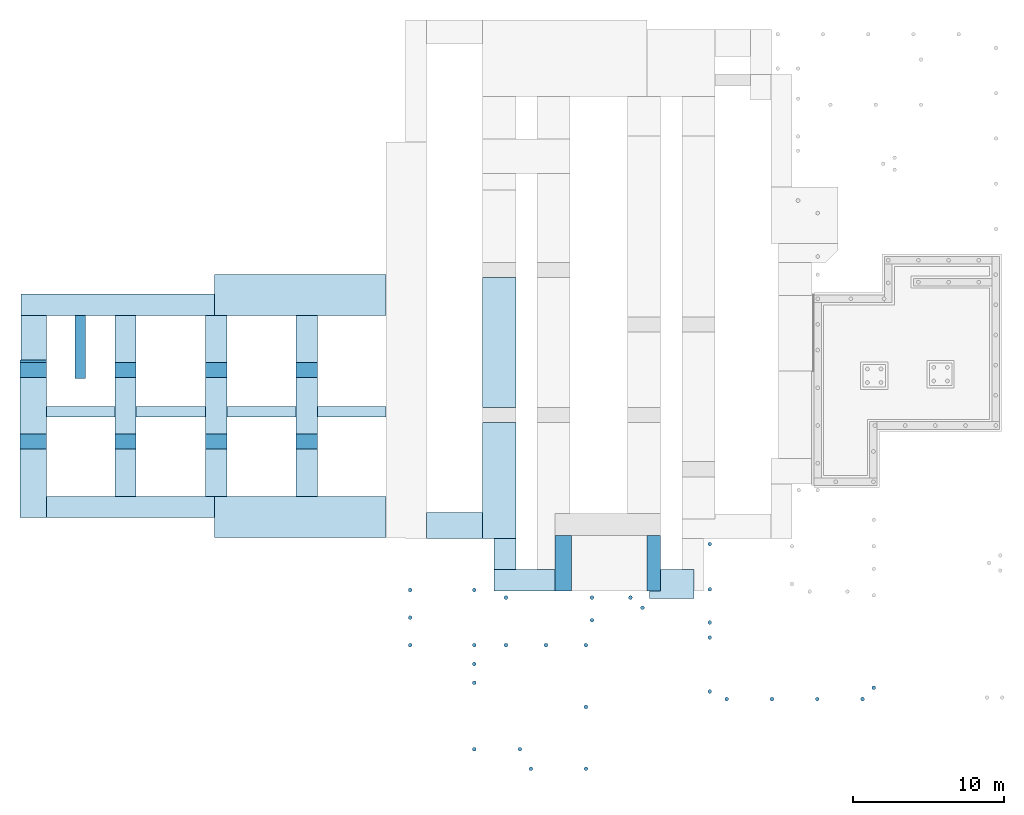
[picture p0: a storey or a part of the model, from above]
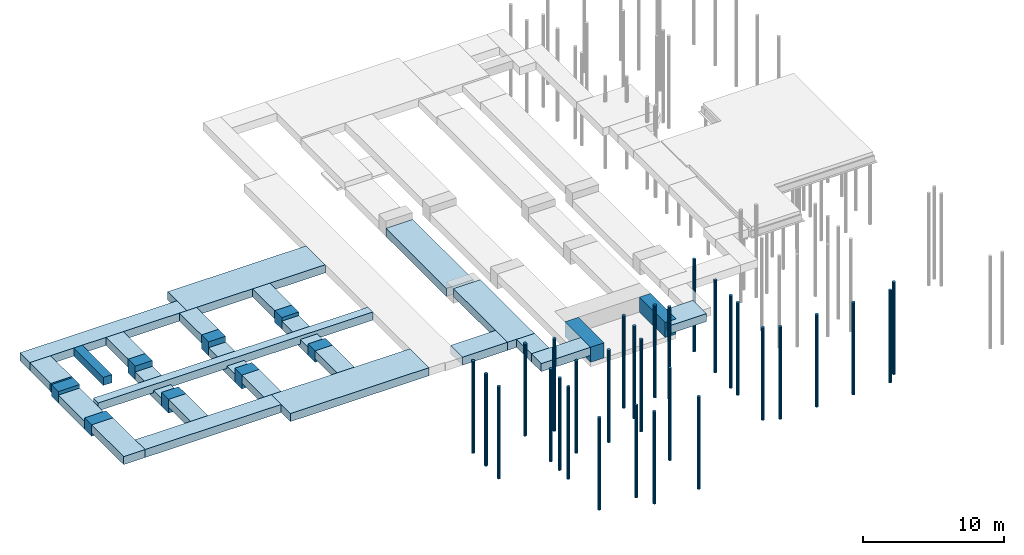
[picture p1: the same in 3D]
Properties of the parts of a building model (IFC4), part 1 of 45

# File
Description: no view
File name: 604-SOKOLOV_ASR_3D_f.ifc
Time: 2023-04-14T09:23:47
Author: Jahodová Jana
Organization: TECHNICO Opava s.r.o., Hradecká 51
Written by: EDMsix Version 2.0.209.92 Dec 12 2020
Made in: Allplan 2022.1 07.06.2022 - 21:35:19

# IfcSite, 3. ASŘ
RefLatitude: 48, 0, 0, 0; RefLongitude: 0, 0, 0, 0

# IfcBuildingStorey (13)
Name | In | Elevation (m)
Půdorys 1.PP | Pavilon B | -3.3
Půdorys 1.NP | Pavilon B | 0
Půdorys 2.NP | Pavilon B | 3.6
Výkopy | Pavilon C | 0
Základy | Pavilon C | -4.4
Půdorys 1.PP | Pavilon C | -3.3
Půdorys 1.NP | Pavilon C | 0
Půdorys 2.NP | Pavilon C | 3.6
Půdorys 3.NP | Pavilon C | 7.2
Půdorys 4.NP | Pavilon C | 10.5
Půdorys 5.NP | Pavilon C | 13.8
Půdorys 6.NP | Pavilon C | 17.8
Půdorys střechy | Pavilon C | 20.83

# IfcSpace (98)
NEMSOK - Typ obestavění: a; Typ plochy DIN 277: N; Typ plochy obytná plocha: WO; BauNVO_Anrechnung_auf_GR: 0; Typ využití DIN 277: NF; BauNVO_Anrechnung_auf_GF: 0; Místnost pod schodištěm (obytná plocha od 2m): 0; Faktor_obytné_plochy_místnosti: 1; Faktor_DIN277: 1; Jednotka: m3; Název_objektu: Místnost
Name | In | LongName | Kód_umístění-označení_podlaží | Name | Profile | Grade | Finish | CogZ | CogX = EndZ | Top_Elevation | EndY | Allright_Stavebni_dil_ID | NetFloorArea (m2) | GrossFloorArea (m2) | GrossWallArea (m2) | NetWallArea (m2) | NetPerimeter (m) | GrossVolume (m3) | NetVolume (m3) | FinishCeilingHeight (m) | FinishFloorHeight (m) | Group
-1.34 | Půdorys 1.PP | CHODBA | 1.PP | P02 | keramická dlažba | TVO, T03 | VSO, KO | LAMINÁT | ŠTUKOVÁ OMÍTKA | 0 | PODLAHOVÁ LIŠTA | 1369Mís0000000006 | 76.24 | 76.24 | 212.28 | 195.812 | 69.6 | 232.532 | 222.621 | 2.92 | 0.1 | ČÁST A | NEMSOK - Status: Nový; Text1: OPĚRNÉ MADLO
-1.35 | Půdorys 1.PP | EEG | 1.PP |  |  |  |  |  |  |  |  | 1369Mís0000000012 | 16.165 | 16.165 | 52.612 | 52.614 | 17.25 | 49.303 | 47.202 | 2.92 | 0.1 | ČÁST A | NEMSOK - Status: Nový; Text1: KERAMICKÝ OBKLAD
-1.39 | Půdorys 1.PP | INTERNÍ AMBULANCE | 1.PP | P02 | keramická dlažba | TVO, T03 | VSO, KO | LAMINÁT | ŠTUKOVÁ OMÍTKA | 0 | PODLAHOVÁ LIŠTA | 1369Mís0000000054 | 15.486 | 15.485 | 50.63 | 50.631 | 16.6 | 47.229 | 45.216 | 2.92 | 0.1 | ČÁST A | NEMSOK - Status: Nový; Text1: KERAMICKÝ OBKLAD
-1.46 | Půdorys 1.PP | PRAKTICKÝ LÉKAŘ | 1.PP | P02 | keramická dlažba | TVO, T03 | VSO, KO | LAMINÁT | ŠTUKOVÁ OMÍTKA | 0 | PODLAHOVÁ LIŠTA | 1369Mís0000000139 | 17.289 | 17.289 | 66.49 | 66.492 | 21.8 | 52.733 | 50.485 | 2.92 | 0.1 | ČÁST A | NEMSOK - Status: Nový; Text1: KERAMICKÝ OBKLAD
-1.47 | Půdorys 1.PP | WC MUŽI PERSONÁL - PŘEDSÍŇ | 1.PP | P02 | keramická dlažba | TVO, T03 | VSO, KO | LAMINÁT | ŠTUKOVÁ OMÍTKA | 0 | PODLAHOVÁ LIŠTA | 1369Mís0000000148 | 1.77 | 1.77 | 16.775 | 16.777 | 5.5 | 5.399 | 5.168 | 2.92 | 0.1 | ČÁST A | NEMSOK - Status: Nový
-1.48 | Půdorys 1.PP | WC MUŽI PERSONÁL | 1.PP | P02 | keramická dlažba | TVO, T03 | VSO, KO | LAMINÁT | ŠTUKOVÁ OMÍTKA | 0 | PODLAHOVÁ LIŠTA | 1369Mís0000000157 | 1.61 | 1.61 | 15.555 | 15.555 | 5.1 | 4.911 | 4.701 | 2.92 | 0.1 | ČÁST A | NEMSOK - Status: Nový
-1.49 | Půdorys 1.PP | PRAKTICKÝ LÉKAŘ - SESTERNA | 1.PP | P02 | keramická dlažba | TVO, T03 | VSO, KO | LAMINÁT | ŠTUKOVÁ OMÍTKA | 0 | PODLAHOVÁ LIŠTA | 1369Mís0000000168 | 20.669 | 20.668 | 63.898 | 63.899 | 20.95 | 63.038 | 60.351 | 2.92 | 0.1 | ČÁST A | NEMSOK - Status: Nový; Text1: KERAMICKÝ OBKLAD
-1.50 | Půdorys 1.PP | MAMOSCREENING - MAMOGRAF | 1.PP | P02 | keramická dlažba | TVO, T03 | VSO, KO | LAMINÁT | ŠTUKOVÁ OMÍTKA | 0 | PODLAHOVÁ LIŠTA | 1369Mís0000000177 | 20.711 | 20.711 | 59.322 | 59.323 | 19.45 | 63.169 | 60.166 | 2.905 | 0.1 | ČÁST A | NEMSOK - Status: Nový; Text1: KERAMICKÝ OBKLAD
-1.51 | Půdorys 1.PP | MAMOSCREENING - POPISOVNA | 1.PP | P02 | keramická dlažba | TVO, T03 | VSO, KO | LAMINÁT | ŠTUKOVÁ OMÍTKA | 0 | PODLAHOVÁ LIŠTA | 1369Mís0000000188 | 17.4 | 17.4 | 54.29 | 54.291 | 17.8 | 53.07 | 50.808 | 2.92 | 0.1 | ČÁST A | NEMSOK - Status: Nový; Text1: KERAMICKÝ OBKLAD
-1.52 | Půdorys 1.PP | MAMOSCREENING - SONO | 1.PP | P02 | keramická dlažba | TVO, T03 | VSO, KO | LAMINÁT | ŠTUKOVÁ OMÍTKA | 0 | PODLAHOVÁ LIŠTA | 1369Mís0000000197 | 17.27 | 17.27 | 50.783 | 50.783 | 16.65 | 52.674 | 50.428 | 2.92 | 0.1 | ČÁST A | NEMSOK - Status: Nový; Text1: KERAMICKÝ OBKLAD
-1.53 | Půdorys 1.PP | MAMOSCREENING - ČEKÁRNA | 1.PP | P02 | keramická dlažba | TVO, T03 | VSO, KO | LAMINÁT | ŠTUKOVÁ OMÍTKA | 0 | PODLAHOVÁ LIŠTA | 1369Mís0000000206 | 36.652 | 36.652 | 119.712 | 119.715 | 39.25 | 111.787 | 107.023 | 2.92 | 0.1 | ČÁST A | NEMSOK - Status: Nový; Text1: KERAMICKÝ OBKLAD
-1.55 | Půdorys 1.PP | HLAVNÍ JISTIČ | 1.PP | P02 | keramická dlažba | TVO, T03 | VSO, KO | LAMINÁT | ŠTUKOVÁ OMÍTKA | 0 | PODLAHOVÁ LIŠTA | 1369Mís0000000215 | 11.2 | 11.199 | 42.7 | 42.7 | 14 | 34.158 | 32.814 | 2.93 | 0.1 | ČÁST A | NEMSOK - Status: Nový
-1.56 | Půdorys 1.PP | WC ŽENY PERSONÁL - PŘEDSÍŇ | 1.PP | P02 | keramická dlažba | TVO, T03 | VSO, KO | LAMINÁT | ŠTUKOVÁ OMÍTKA | 0 | PODLAHOVÁ LIŠTA | 1369Mís0000000224 | 1.93 | 1.93 | 17.049 | 17.05 | 5.59 | 5.886 | 5.635 | 2.92 | 0.1 | ČÁST A | NEMSOK - Status: Nový
-1.56a | Půdorys 1.PP | WC ŽENY PERSONÁL | 1.PP | P02 | keramická dlažba | TVO, T03 | VSO, KO | LAMINÁT | ŠTUKOVÁ OMÍTKA | 0 | PODLAHOVÁ LIŠTA | 1369Mís0000000233 | 1.537 | 1.537 | 15.128 | 15.129 | 4.96 | 4.689 | 4.489 | 2.92 | 0.1 | ČÁST A | NEMSOK - Status: Nový
-1.40 | Půdorys 1.PP | WC MUŽI - PŘEDSÍŇ | 1.PP | P02 | keramická dlažba | TVO, T03 | VSO, KO | LAMINÁT | ŠTUKOVÁ OMÍTKA | 0 | PODLAHOVÁ LIŠTA | 1369Mís0000000367 | 4.923 | 4.922 | 33.855 | 33.856 | 11.1 | 15.014 | 14.373 | 2.92 | 0.1 | ČÁST A | NEMSOK - Status: Nový
-1.41 | Půdorys 1.PP | WC MUŽI | 1.PP | P02 | keramická dlažba | TVO, T03 | VSO, KO | LAMINÁT | ŠTUKOVÁ OMÍTKA | 0 | PODLAHOVÁ LIŠTA | 1369Mís0000000378 | 1.148 | 1.148 | 13.268 | 10.523 | 4.35 | 3.5 | 3.351 | 2.92 | 0.1 | ČÁST A | NEMSOK - Status: Nový
-1.42 | Půdorys 1.PP | WC ZTP | 1.PP | P02 | keramická dlažba | TVO, T03 | VSO, KO | LAMINÁT | ŠTUKOVÁ OMÍTKA | 0 | PODLAHOVÁ LIŠTA | 1369Mís0000000387 | 4.07 | 4.07 | 26.535 | 26.536 | 8.7 | 12.413 | 11.884 | 2.92 | 0.1 | ČÁST A | NEMSOK - Status: Nový
-1.43 | Půdorys 1.PP | WC ŽENY - PŘEDSÍŇ | 1.PP | P02 | keramická dlažba | TVO, T03 | VSO, KO | LAMINÁT | ŠTUKOVÁ OMÍTKA | 0 | PODLAHOVÁ LIŠTA | 1369Mís0000000396 | 2.43 | 2.43 | 19.215 | 19.215 | 6.3 | 7.412 | 7.096 | 2.92 | 0.1 | ČÁST A | NEMSOK - Status: Nový
-1.44 | Půdorys 1.PP | WC ŽENY | 1.PP | P02 | keramická dlažba | TVO, T03 | VSO, KO | LAMINÁT | ŠTUKOVÁ OMÍTKA | 0 | PODLAHOVÁ LIŠTA | 1369Mís0000000405 | 1.485 | 1.485 | 15.555 | 15.555 | 5.1 | 4.529 | 4.336 | 2.92 | 0.1 | ČÁST A | NEMSOK - Status: Nový
-1.45 | Půdorys 1.PP | WC ŽENY | 1.PP | P02 | keramická dlažba | TVO, T03 | VSO, KO | LAMINÁT | ŠTUKOVÁ OMÍTKA | 0 | PODLAHOVÁ LIŠTA | 1369Mís0000000416 | 2.025 | 2.025 | 19.825 | 19.826 | 6.5 | 6.176 | 5.913 | 2.92 | 0.1 | ČÁST A | NEMSOK - Status: Nový
-1.54 | Půdorys 1.PP | TECHNOLOGIE | 1.PP | P02 | keramická dlažba | TVO, T03 | VSO, KO | LAMINÁT | ŠTUKOVÁ OMÍTKA | 0 | PODLAHOVÁ LIŠTA | 1369Mís0000000514 | 1.305 | 1.305 | 15.402 | 15.403 | 5.05 | 3.98 | 3.824 | 2.93 | 0.1 | ČÁST A | NEMSOK - Status: Nový
-1.05 | Půdorys 1.PP | STROJOVNA VZT | 1.PP | P02 | keramická dlažba | TVO, T03 | VSO, KO | LAMINÁT | ŠTUKOVÁ OMÍTKA | 0 | PODLAHOVÁ LIŠTA | 1369Mís0000001178 | 22.984 | 22.985 | 64.163 | 64.165 | 21.75 | 67.806 | 64.359 | 2.8 | 0.1 | ČÁST A | NEMSOK - Text1: AKUSTICKÝ OBKLAD
-1.57 | Půdorys 1.PP | ÚKLIDOVÁ KOMORA | 1.PP | P02 | keramická dlažba | TVO, T03 | VSO, KO | LAMINÁT | ŠTUKOVÁ OMÍTKA | 0 | PODLAHOVÁ LIŠTA | 1369Mís0000001551 | 3.026 | 3.026 | 21.777 | 21.778 | 7.14 | 9.229 | 8.836 | 2.92 | 0.1 | ČÁST A | NEMSOK - Status: Nový
-1.41 | Půdorys 1.PP | WC MUŽI | 1.PP | P02 | keramická dlažba | TVO, T03 | VSO, KO | LAMINÁT | ŠTUKOVÁ OMÍTKA | 0 | PODLAHOVÁ LIŠTA | 1369Mís0000001767 | 3.47 | 3.47 | 24.095 | 21.351 | 7.9 | 10.584 | 10.132 | 2.92 | 0.1 | ČÁST A | NEMSOK - Status: Nový
-1.38 | Půdorys 1.PP | ČEKÁRNA | 1.PP | P02 | keramická dlažba | TVO, T03 | VSO, KO | LAMINÁT | ŠTUKOVÁ OMÍTKA | 0 | PODLAHOVÁ LIŠTA | 1369Mís0000000043 | 28.459 | 28.459 | 67.862 | 51.393 | 22.25 | 86.801 | 83.101 | 2.92 | 0.1 | ČÁST A | NEMSOK - Status: Nový
-1.36 | Půdorys 1.PP | EMG | 1.PP | P02 | keramická dlažba | TVO, T03 | VSO, KO | LAMINÁT | ŠTUKOVÁ OMÍTKA | 0 | PODLAHOVÁ LIŠTA | 1369Mís0000000023 | 16.165 | 16.165 | 52.613 | 52.614 | 17.25 | 49.303 | 47.202 | 2.92 | 0.1 | ČÁST A | NEMSOK - Status: Nový; Text1: KERAMICKÝ OBKLAD
-1.37 | Půdorys 1.PP | SONO | 1.PP | P02 | keramická dlažba | TVO, T03 | VSO, KO | LAMINÁT | ŠTUKOVÁ OMÍTKA | 0 | PODLAHOVÁ LIŠTA | 1369Mís0000000034 | 24.09 | 24.09 | 61.915 | 61.917 | 20.3 | 73.475 | 70.343 | 2.92 | 0.1 | ČÁST A | NEMSOK - Status: Nový; Text1: KERAMICKÝ OBKLAD
-1.58 | Půdorys 1.PP | CHODBA | 1.PP | P02 | keramická dlažba | TVO, T03 | VSO, KO | LAMINÁT | ŠTUKOVÁ OMÍTKA | 0 | PODLAHOVÁ LIŠTA | 1369Mís0000000539 | 7.41 | 7.41 | 40.412 | 36.753 | 13.25 | 22.601 | 21.526 | 2.905 | 0.1 | ČÁST B
-1.64 | Půdorys 1.PP | CHODBA | 1.PP | P02 | keramická dlažba | TVO, T03 | VSO, KO | LAMINÁT | ŠTUKOVÁ OMÍTKA | 0 | PODLAHOVÁ LIŠTA | 1369Mís0000000548 | 9.076 | 9.075 | 45.597 | 45.598 | 14.95 | 27.679 | 26.318 | 2.9 | 0.1 | ČÁST B
-1.60 | Půdorys 1.PP | INSTALAČNÍ CHODBA VZT | 1.PP | P02 | keramická dlažba | TVO, T03 | VSO, KO | LAMINÁT | ŠTUKOVÁ OMÍTKA | 0 | PODLAHOVÁ LIŠTA | 1369Mís0000000557 | 8.352 | 8.352 | 52.787 | 52.788 | 16.242 | 27.145 | 24.598 | 2.945 | 0.3 | ČÁST B
-1.61 | Půdorys 1.PP | KANCELÁŘ VRCHNÍ SESTRY | 1.PP | P02 | keramická dlažba | TVO, T03 | VSO, KO | LAMINÁT | ŠTUKOVÁ OMÍTKA | 0 | PODLAHOVÁ LIŠTA | 1369Mís0000000566 | 16.75 | 16.75 | 54.275 | 54.275 | 16.7 | 54.438 | 48.91 | 2.92 | 0.3 | ČÁST B | NEMSOK - Text1: KERAMICKÝ OBKLAD
-1.62 | Půdorys 1.PP | DENNÍ MÍSTNOST | 1.PP | P02 | keramická dlažba | TVO, T03 | VSO, KO | LAMINÁT | ŠTUKOVÁ OMÍTKA | 0 | PODLAHOVÁ LIŠTA | 1369Mís0000000575 | 28.32 | 28.32 | 78 | 78.002 | 24 | 92.04 | 82.694 | 2.92 | 0.3 | ČÁST B | NEMSOK - Text1: KERAMICKÝ OBKLAD
-1.63 | Půdorys 1.PP | STROJOVNA VZT | 1.PP | P02 | keramická dlažba | TVO, T03 | VSO, KO | LAMINÁT | ŠTUKOVÁ OMÍTKA | 0 | PODLAHOVÁ LIŠTA | 1369Mís0000000584 | 51.486 | 51.486 | 144.56 | 144.56 | 44.48 | 167.331 | 149.311 | 2.9 | 0.3 | ČÁST B
-1.59 | Půdorys 1.PP | TECHNICKÁ MÍSTNOST ELEKTRO | 1.PP | P02 | keramická dlažba | TVO, T03 | VSO, KO | LAMINÁT | ŠTUKOVÁ OMÍTKA | 0 | PODLAHOVÁ LIŠTA | 1369Mís0000000599 | 22.61 | 22.61 | 59.475 | 59.476 | 19.5 | 68.961 | 66.248 | 2.93 | 0.1 | ČÁST B | NEMSOK - Text1: DOPLNĚNÍ OMÍTKY
-1.19 | Půdorys 1.PP | SKLAD STERILNÍHO MATERIÁLU | 1.PP | P02 | keramická dlažba | TVO, T03 | VSO, KO | LAMINÁT | ŠTUKOVÁ OMÍTKA | 0 | PODLAHOVÁ LIŠTA | 1369Mís0000000879 | 85.169 | 85.167 | 122.915 | 122.918 | 40.3 | 259.761 | 248.69 | 2.92 | 0.1 | ČÁST B | NEMSOK - Status: Nespecifikovaný; Text1: DOPLNĚNÍ KERAM. OBKLADU
-1.58 | Půdorys 1.PP | CHODBA | 1.PP | P02 | keramická dlažba | TVO, T03 | VSO, KO | LAMINÁT | ŠTUKOVÁ OMÍTKA | 0 | PODLAHOVÁ LIŠTA | 1369Mís0000001088 | 13.982 | 13.982 | 65.325 | 61.667 | 20.1 | 45.441 | 40.616 | 2.905 | 0.3 | ČÁST B
-1.02 | Půdorys 1.PP | CHODBA | 1.PP | P02 | keramická dlažba | TVO, T03 | VSO, KO | LAMINÁT | ŠTUKOVÁ OMÍTKA | 0 | PODLAHOVÁ LIŠTA | 1369Mís0000001285 | 41.014 | 41.014 | 117.41 | 117.412 | 39.8 | 120.991 | 119.556 | 2.915 | 0.005 | ČÁST B | NEMSOK - Text1: DŘEVĚNÉ MADLO
1.01 | Půdorys 1.NP | SPOJOVACÍ CHODBA | 1.NP | P02 | keramická dlažba | TVO, T03 | VSO, KO | LAMINÁT | ŠTUKOVÁ OMÍTKA | 0 | PODLAHOVÁ LIŠTA | 1469Mís0000000353 | 48.806 | 48.805 | 149.912 | 139.528 | 44.75 | 163.497 | 157.152 | 3.22 | 0.1 | KAVÁRNA
K1.09 | Půdorys 1.NP | PŘÍPRAVNA STUDENÉ KUCHYNĚ | 1.NP | P02 | keramická dlažba | TVO, T03 | VSO, KO | LAMINÁT | ŠTUKOVÁ OMÍTKA | 0 | PODLAHOVÁ LIŠTA | 1469Mís0000000427 | 19.335 | 19.334 | 74.55 | 74.551 | 21 | 68.636 | 62.256 | 3.22 | 0.3 | KAVÁRNA
K1.10 | Půdorys 1.NP | SKLAD | 1.NP | P02 | keramická dlažba | TVO, T03 | VSO, KO | LAMINÁT | ŠTUKOVÁ OMÍTKA | 0 | PODLAHOVÁ LIŠTA | 1469Mís0000000439 | 6.919 | 6.919 | 38.517 | 38.518 | 10.85 | 24.562 | 22.278 | 3.22 | 0.3 | KAVÁRNA
K1.12 | Půdorys 1.NP | ÚKLID | 1.NP | P02 | keramická dlažba | TVO, T03 | VSO, KO | LAMINÁT | ŠTUKOVÁ OMÍTKA | 0 | PODLAHOVÁ LIŠTA | 1469Mís0000000448 | 2.031 | 2.031 | 20.413 | 20.413 | 5.75 | 7.211 | 6.541 | 3.22 | 0.3 | KAVÁRNA
K1.11 | Půdorys 1.NP | CHODBA | 1.NP | P02 | keramická dlažba | TVO, T03 | VSO, KO | LAMINÁT | ŠTUKOVÁ OMÍTKA | 0 | PODLAHOVÁ LIŠTA | 1469Mís0000000459 | 5.025 | 5.025 | 34.435 | 34.435 | 9.7 | 17.839 | 16.181 | 3.22 | 0.3 | KAVÁRNA
K1.13 | Půdorys 1.NP | ŠATNA | 1.NP | P02 | keramická dlažba | TVO, T03 | VSO, KO | LAMINÁT | ŠTUKOVÁ OMÍTKA | 0 | PODLAHOVÁ LIŠTA | 1469Mís0000000470 | 3.5 | 3.5 | 26.625 | 26.625 | 7.5 | 12.425 | 11.27 | 3.22 | 0.3 | KAVÁRNA
K1.14a | Půdorys 1.NP | WC ZAMĚSTNANCI | 1.NP | P02 | keramická dlažba | TVO, T03 | VSO, KO | LAMINÁT | ŠTUKOVÁ OMÍTKA | 0 | PODLAHOVÁ LIŠTA | 1469Mís0000000481 | 1.327 | 1.327 | 16.862 | 16.863 | 4.75 | 4.713 | 4.275 | 3.22 | 0.3 | KAVÁRNA
K1.14 | Půdorys 1.NP | WC PŘEDSÍŇ ZAMĚSTNANCI | 1.NP | P02 | keramická dlažba | TVO, T03 | VSO, KO | LAMINÁT | ŠTUKOVÁ OMÍTKA | 0 | PODLAHOVÁ LIŠTA | 1469Mís0000000490 | 3.631 | 3.631 | 27.157 | 27.158 | 7.65 | 12.891 | 11.693 | 3.22 | 0.3 | KAVÁRNA
K1.01 | Půdorys 1.NP | HALA | 1.NP | P02 | keramická dlažba | TVO, T03 | VSO, KO | LAMINÁT | ŠTUKOVÁ OMÍTKA | 0 | PODLAHOVÁ LIŠTA | 1469Mís0000000527 | 10.694 | 10.694 | 44.053 | 38.024 | 13.15 | 35.824 | 34.434 | 3.22 | 0.1 | KAVÁRNA
K1.02 | Půdorys 1.NP | SKLAD NÁPOJŮ | 1.NP | P02 | keramická dlažba | TVO, T03 | VSO, KO | LAMINÁT | ŠTUKOVÁ OMÍTKA | 0 | PODLAHOVÁ LIŠTA | 1469Mís0000000538 | 2.219 | 2.219 | 20.1 | 20.101 | 6 | 7.435 | 7.146 | 3.22 | 0.1 | KAVÁRNA
K1.03 | Půdorys 1.NP | SKLAD OBALŮ | 1.NP | P02 | keramická dlažba | TVO, T03 | VSO, KO | LAMINÁT | ŠTUKOVÁ OMÍTKA | 0 | PODLAHOVÁ LIŠTA | 1469Mís0000000549 | 2.275 | 2.275 | 20.938 | 20.939 | 6.25 | 7.621 | 7.326 | 3.22 | 0.1 | KAVÁRNA
K1.06 | Půdorys 1.NP | RANNÍ SKLAD | 1.NP | P02 | keramická dlažba | TVO, T03 | VSO, KO | LAMINÁT | ŠTUKOVÁ OMÍTKA | 0 | PODLAHOVÁ LIŠTA | 1469Mís0000000558 | 5.012 | 5.011 | 34.337 | 34.339 | 10.25 | 16.788 | 16.136 | 3.22 | 0.1 | KAVÁRNA
K1.04 | Půdorys 1.NP | WC MUŽI - PŘEDSÍŇ | 1.NP | P02 | keramická dlažba | TVO, T03 | VSO, KO | LAMINÁT | ŠTUKOVÁ OMÍTKA | 0 | PODLAHOVÁ LIŠTA | 1469Mís0000000569 | 2.345 | 2.345 | 20.603 | 20.603 | 6.15 | 7.856 | 7.551 | 3.22 | 0.1 | KAVÁRNA
K1.05 | Půdorys 1.NP | WC ŽENY | 1.NP | P02 | keramická dlažba | TVO, T03 | VSO, KO | LAMINÁT | ŠTUKOVÁ OMÍTKA | 0 | PODLAHOVÁ LIŠTA | 1469Mís0000000580 | 4.236 | 4.236 | 28.81 | 28.811 | 8.6 | 14.191 | 13.641 | 3.22 | 0.1 | KAVÁRNA
K1.04a | Půdorys 1.NP | WC MUŽI | 1.NP | P02 | keramická dlažba | TVO, T03 | VSO, KO | LAMINÁT | ŠTUKOVÁ OMÍTKA | 0 | PODLAHOVÁ LIŠTA | 1469Mís0000000589 | 1.575 | 1.575 | 17.253 | 17.253 | 5.15 | 5.276 | 5.072 | 3.22 | 0.1 | KAVÁRNA
K1.08 | Půdorys 1.NP | KAVÁRNA - PRODEJ | 1.NP | P02 | keramická dlažba | TVO, T03 | VSO, KO | LAMINÁT | ŠTUKOVÁ OMÍTKA | 0 | PODLAHOVÁ LIŠTA | 1469Mís0000000623 | 14.505 | 14.506 | 56.591 | 28.514 | 15.941 | 51.497 | 46.709 | 3.22 | 0.3 | KAVÁRNA
K1.07 | Půdorys 1.NP | KAVÁRNA | 1.NP | P02 | keramická dlažba | TVO, T03 | VSO, KO | LAMINÁT | ŠTUKOVÁ OMÍTKA | 0 | PODLAHOVÁ LIŠTA | 1469Mís0000000634 | 42.221 | 42.222 | 113.341 | 79.236 | 31.927 | 149.887 | 135.952 | 3.22 | 0.3 | KAVÁRNA
K1.01 | Půdorys 1.NP | HALA | 1.NP | P02 | keramická dlažba | TVO, T03 | VSO, KO | LAMINÁT | ŠTUKOVÁ OMÍTKA | 0 | PODLAHOVÁ LIŠTA | 1469Mís0000002691 | 0.72 | 0.72 | 14.74 | 2.68 | 4.4 | 2.412 | 2.318 | 3.22 | 0.1 | KAVÁRNA
1.01 | Půdorys 1.NP | SPOJOVACÍ CHODBA | 1.NP | P02 | keramická dlažba | TVO, T03 | VSO, KO | LAMINÁT | ŠTUKOVÁ OMÍTKA | 0 | PODLAHOVÁ LIŠTA | 1469Mís0000002742 | 1.24 | 1.24 | 23.45 | 2.68 | 7 | 4.154 | 3.993 | 3.22 | 0.1 | KAVÁRNA
K1.14b | Půdorys 1.NP | SPRCHA ZAMĚSTNANCI | 1.NP | P02 | keramická dlažba | TVO, T03 | VSO, KO | LAMINÁT | ŠTUKOVÁ OMÍTKA | 0 | PODLAHOVÁ LIŠTA | 1469Mís0000003032 | 1.63 | 1.63 | 18.993 | 18.992 | 5.35 | 5.786 | 5.249 | 3.22 | 0.3 | KAVÁRNA
1.24 | Půdorys 1.NP | ÚNIKOVÉ SCHODIŠTĚ | 1.NP | P02 | keramická dlažba | TVO, T03 | VSO, KO | LAMINÁT | ŠTUKOVÁ OMÍTKA | 0 | PODLAHOVÁ LIŠTA | 1469Mís0000000175 | 22.116 | 22.116 | 69.875 | 69.876 | 21.5 | 71.876 | 71.323 | 3.225 | 0.005 | URGENT | NEMSOK - Status: Nový; Text1: STUPNĚ - TERACO
1.01a | Půdorys 1.NP | ZÁDVEŘÍ | 1.NP | P02 | keramická dlažba | TVO, T03 | VSO, KO | LAMINÁT | ŠTUKOVÁ OMÍTKA | 0 | PODLAHOVÁ LIŠTA | 1469Mís0000000893 | 13.455 | 13.455 | 65.49 | 65.49 | 17.7 | 49.783 | 45.343 | 3.37 | 0.3 | URGENT
1.01b | Půdorys 1.NP | ČEKÁRNA | 1.NP | P02 | keramická dlažba | TVO, T03 | VSO, KO | LAMINÁT | ŠTUKOVÁ OMÍTKA | 0 | PODLAHOVÁ LIŠTA | 1469Mís0000000906 | 76.088 | 76.088 | 142.598 | 132.213 | 38.54 | 281.526 | 256.417 | 3.37 | 0.3 | URGENT
1.02 | Půdorys 1.NP | TRIÁŽ | 1.NP | P02 | keramická dlažba | TVO, T03 | VSO, KO | LAMINÁT | ŠTUKOVÁ OMÍTKA | 0 | PODLAHOVÁ LIŠTA | 1469Mís0000000915 | 21.736 | 21.736 | 69.412 | 69.412 | 18.76 | 80.423 | 73.25 | 3.37 | 0.3 | URGENT | NEMSOK - Text1: ACROVINYLOVÝ+KERM. OBKLAD
1.03 | Půdorys 1.NP | CHODBA | 1.NP | P02 | keramická dlažba | TVO, T03 | VSO, KO | LAMINÁT | ŠTUKOVÁ OMÍTKA | 0 | PODLAHOVÁ LIŠTA | 1469Mís0000000924 | 26.681 | 26.681 | 78.242 | 65.925 | 22.04 | 94.717 | 85.913 | 3.22 | 0.3 | URGENT
1.08 | Půdorys 1.NP | CHODBA | 1.NP | P02 | keramická dlažba | TVO, T03 | VSO, KO | LAMINÁT | ŠTUKOVÁ OMÍTKA | 0 | PODLAHOVÁ LIŠTA | 1469Mís0000000933 | 50.913 | 50.913 | 116.474 | 78.491 | 32.81 | 180.739 | 171.574 | 3.37 | 0.15 | URGENT | NEMSOK - Text1: KERAMICKÝ OBKLAD
1.09 | Půdorys 1.NP | SESTERNA | 1.NP | P02 | keramická dlažba | TVO, T03 | VSO, KO | 0 | 0 | 0 | 0 | 1469Mís0000000993 | 26.989 | 26.989 | 90.762 | 10.628 | 24.53 | 99.86 | 90.954 | 3.37 | 0.3 | URGENT
1.10 | Půdorys 1.NP | BOX - IZOLACE | 1.NP | P02 | keramická dlažba | TVO, T03 | VSO, KO | LAMINÁT | ŠTUKOVÁ OMÍTKA | 0 | PODLAHOVÁ LIŠTA | 1469Mís0000001025 | 24.903 | 24.902 | 80.94 | 80.942 | 22.8 | 88.404 | 83.922 | 3.37 | 0.15 | URGENT
1.11 | Půdorys 1.NP | BOX | 1.NP | P02 | keramická dlažba | TVO, T03 | VSO, KO | 0 | 0 | 0 | 0 | 1469Mís0000001034 | 12.41 | 12.41 | 50.055 | 50.055 | 14.1 | 44.056 | 41.822 | 3.37 | 0.15 | URGENT
1.12 | Půdorys 1.NP | BOX | 1.NP | P02 | keramická dlažba | TVO, T03 | VSO, KO | 0 | 0 | 0 | 0 | 1469Mís0000001063 | 12.41 | 12.41 | 50.055 | 50.055 | 14.1 | 44.056 | 41.822 | 3.37 | 0.15 | URGENT
1.13 | Půdorys 1.NP | BOX | 1.NP | P02 | keramická dlažba | TVO, T03 | VSO, KO | 0 | 0 | 0 | 0 | 1469Mís0000001072 | 10.585 | 10.585 | 48.47 | 35.513 | 13.1 | 39.165 | 35.671 | 3.37 | 0.3 | URGENT
1.14 | Půdorys 1.NP | BOX | 1.NP | P02 | keramická dlažba | TVO, T03 | VSO, KO | 0 | 0 | 0 | 0 | 1469Mís0000001081 | 12.41 | 12.41 | 52.17 | 52.17 | 14.1 | 45.917 | 41.822 | 3.37 | 0.3 | URGENT
1.15 | Půdorys 1.NP | BOX | 1.NP | P02 | keramická dlažba | TVO, T03 | VSO, KO | 0 | 0 | 0 | 0 | 1469Mís0000001090 | 11.744 | 11.744 | 49.668 | 49.669 | 13.424 | 43.453 | 39.577 | 3.37 | 0.3 | URGENT
1.16 | Půdorys 1.NP | BOX | 1.NP | P02 | keramická dlažba | TVO, T03 | VSO, KO | 0 | 0 | 0 | 0 | 1469Mís0000001099 | 23.561 | 23.562 | 73.462 | 73.461 | 19.854 | 87.178 | 79.402 | 3.37 | 0.3 | URGENT
1.17 | Půdorys 1.NP | ČISTÁ ČISTIČKA | 1.NP | P02 | keramická dlažba | TVO, T03 | VSO, KO | 0 | 0 | 0 | 0 | 1469Mís0000001122 | 12.015 | 12.015 | 52.91 | 52.91 | 14.3 | 44.456 | 40.491 | 3.37 | 0.3 | URGENT
1.18 | Půdorys 1.NP | DENNÍ MÍSTNOST | 1.NP | P02 | keramická dlažba | TVO, T03 | VSO, KO | 0 | 0 | 0 | 0 | 1469Mís0000001131 | 13.239 | 13.239 | 55.13 | 55.132 | 14.9 | 48.983 | 44.614 | 3.37 | 0.3 | URGENT | NEMSOK - Text1: KERAMICKÝ OBKLAD
1.19 | Půdorys 1.NP | LÉKAŘSKÝ POKOJ | 1.NP | P02 | keramická dlažba | TVO, T03 | VSO, KO | 0 | 0 | 0 | 0 | 1469Mís0000001140 | 11.271 | 11.271 | 57.128 | 57.128 | 15.44 | 41.703 | 37.983 | 3.37 | 0.3 | URGENT
1.20 | Půdorys 1.NP | CHODBA | 1.NP | P02 | keramická dlažba | TVO, T03 | VSO, KO | 0 | 0 | 0 | 0 | 1469Mís0000001149 | 25.994 | 25.994 | 101.539 | 96.514 | 30.31 | 87.079 | 83.7 | 3.22 | 0.1 | URGENT
1.21 | Půdorys 1.NP | WC PACIENTI | 1.NP | P02 | keramická dlažba | TVO, T03 | VSO, KO | 0 | 0 | 0 | 0 | 1469Mís0000001158 | 3.737 | 3.737 | 27.169 | 27.169 | 8.11 | 12.517 | 12.032 | 3.22 | 0.1 | URGENT
1.22 | Půdorys 1.NP | WC PACIENTI | 1.NP | P02 | keramická dlažba | TVO, T03 | VSO, KO | 0 | 0 | 0 | 0 | 1469Mís0000001176 | 3.348 | 3.349 | 24.957 | 24.958 | 7.45 | 11.218 | 10.783 | 3.22 | 0.1 | URGENT
1.23 | Půdorys 1.NP | ÚKLIDOVÁ KOMORA | 1.NP | P02 | keramická dlažba | TVO, T03 | VSO, KO | 0 | 0 | 0 | 0 | 1469Mís0000001194 | 2.754 | 2.754 | 24.623 | 24.624 | 7.35 | 9.225 | 8.867 | 3.22 | 0.1 | URGENT
1.04 | Půdorys 1.NP | CHODBA | 1.NP | P02 | keramická dlažba | TVO, T03 | VSO, KO | LAMINÁT | ŠTUKOVÁ OMÍTKA | 0 | PODLAHOVÁ LIŠTA | 1469Mís0000001205 | 22.131 | 22.13 | 67.033 | 67.034 | 20.01 | 74.137 | 71.261 | 3.22 | 0.1 | URGENT
1.05 | Půdorys 1.NP | PŘÍLEŽITOSTNÁ AMBULANCE | 1.NP | P02 | keramická dlažba | TVO, T03 | VSO, KO | LAMINÁT | ŠTUKOVÁ OMÍTKA | 0 | PODLAHOVÁ LIŠTA | 1469Mís0000001216 | 25.261 | 25.261 | 87.904 | 87.906 | 26.24 | 84.624 | 81.339 | 3.22 | 0.1 | URGENT | NEMSOK - Text1: KERAMICKÝ OBKLAD
1.06 | Půdorys 1.NP | OČISTA PACIENTA | 1.NP | P02 | keramická dlažba | TVO, T03 | VSO, KO | LAMINÁT | ŠTUKOVÁ OMÍTKA | 0 | PODLAHOVÁ LIŠTA | 1469Mís0000001225 | 16.342 | 16.342 | 60.099 | 60.1 | 17.94 | 54.745 | 52.62 | 3.22 | 0.1 | URGENT
1.07 | Půdorys 1.NP | SKLAD MATERIÁLU | 1.NP | P02 | keramická dlažba | TVO, T03 | VSO, KO | LAMINÁT | ŠTUKOVÁ OMÍTKA | 0 | PODLAHOVÁ LIŠTA | 1469Mís0000001234 | 15.989 | 15.989 | 61.272 | 61.271 | 18.29 | 53.564 | 51.485 | 3.22 | 0.1 | URGENT
1.27 | Půdorys 1.NP | ŠATNA ŽENY | 1.NP | P02 | keramická dlažba | TVO, T03 | VSO, KO | 0 | 0 | 0 | 0 | 1469Mís0000001243 | 28.369 | 28.366 | 87.971 | 87.974 | 26.26 | 95.025 | 91.337 | 3.22 | 0.1 | URGENT
1.28 | Půdorys 1.NP | WC ŽENY - PŘEDSÍŇ | 1.NP | P02 | keramická dlažba | TVO, T03 | VSO, KO | 0 | 0 | 0 | 0 | 1469Mís0000001252 | 2.291 | 2.291 | 20.938 | 20.938 | 6.25 | 7.676 | 7.378 | 3.22 | 0.1 | URGENT
1.28a | Půdorys 1.NP | WC ŽENY | 1.NP | P02 | keramická dlažba | TVO, T03 | VSO, KO | 0 | 0 | 0 | 0 | 1469Mís0000001261 | 2.21 | 2.21 | 21.44 | 21.441 | 6.4 | 7.403 | 7.117 | 3.22 | 0.1 | URGENT
1.28b | Půdorys 1.NP | SPRCHA ŽENY | 1.NP | P02 | keramická dlažba | TVO, T03 | VSO, KO | 0 | 0 | 0 | 0 | 1469Mís0000001270 | 1.95 | 1.95 | 19.765 | 19.765 | 5.9 | 6.533 | 6.279 | 3.22 | 0.1 | URGENT
1.25 | Půdorys 1.NP | ŠATNA MUŽI | 1.NP | P02 | keramická dlažba | TVO, T03 | VSO, KO | 0 | 0 | 0 | 0 | 1469Mís0000001279 | 11.862 | 11.862 | 49.714 | 49.716 | 14.84 | 39.737 | 38.195 | 3.22 | 0.1 | URGENT
1.26 | Půdorys 1.NP | WC MUŽI - PŘEDSÍŇ | 1.NP | P02 | keramická dlažba | TVO, T03 | VSO, KO | 0 | 0 | 0 | 0 | 1469Mís0000001290 | 2.913 | 2.913 | 24.288 | 24.288 | 7.25 | 9.757 | 9.379 | 3.22 | 0.1 | URGENT
1.26a | Půdorys 1.NP | WC MUŽI | 1.NP | P02 | keramická dlažba | TVO, T03 | VSO, KO | 0 | 0 | 0 | 0 | 1469Mís0000001299 | 1.058 | 1.057 | 13.903 | 13.903 | 4.15 | 3.543 | 3.405 | 3.22 | 0.1 | URGENT
1.30 | Půdorys 1.NP | CHODBA | 1.NP | P02 | keramická dlažba | TVO, T03 | VSO, KO | 0 | 0 | 0 | 0 | 1469Mís0000001308 | 49.32 | 49.32 | 136.513 | 136.514 | 40.75 | 165.222 | 158.811 | 3.22 | 0.1 | URGENT | NEMSOK - Text1: SVODIDLO
1.29 | Půdorys 1.NP | ŠPINAVÁ ČISTIČKA | 1.NP | P02 | keramická dlažba | TVO, T03 | VSO, KO | 0 | 0 | 0 | 0 | 1469Mís0000001319 | 18.302 | 18.302 | 74.337 | 74.339 | 22.19 | 61.313 | 58.934 | 3.22 | 0.1 | URGENT
1.31 | Půdorys 1.NP | ROZVODNA ELEKTRO | 1.NP | P02 | keramická dlažba | TVO, T03 | VSO, KO | 0 | 0 | 0 | 0 | 1469Mís0000001328 | 6.512 | 6.513 | 38.056 | 38.057 | 11.36 | 21.817 | 21.036 | 3.23 | 0.1 | URGENT
1.33 | Půdorys 1.NP | SKLAD | 1.NP | P02 | keramická dlažba | TVO, T03 | VSO, KO | 0 | 0 | 0 | 0 | 1469Mís0000001837 | 3.725 | 3.725 | 30.081 | 30.081 | 8.13 | 13.781 | 12.589 | 3.38 | 0.3 | URGENT
1.03 | Půdorys 1.NP | CHODBA | 1.NP | P02 | keramická dlažba | TVO, T03 | VSO, KO | LAMINÁT | ŠTUKOVÁ OMÍTKA | 0 | PODLAHOVÁ LIŠTA | 1469Mís0000002408 | 12.737 | 12.737 | 58.238 | 45.92 | 15.74 | 47.125 | 42.922 | 3.37 | 0.3 | URGENT
1.08 | Půdorys 1.NP | CHODBA | 1.NP | P02 | keramická dlažba | TVO, T03 | VSO, KO | LAMINÁT | ŠTUKOVÁ OMÍTKA | 0 | PODLAHOVÁ LIŠTA | 1469Mís0000002452 | 74.804 | 74.803 | 239.789 | 123.895 | 64.808 | 276.773 | 252.088 | 3.37 | 0.3 | URGENT | NEMSOK - Text1: KERAMICKÝ OBKLAD
1.13 | Půdorys 1.NP | BOX | 1.NP | P02 | keramická dlažba | TVO, T03 | VSO, KO | 0 | 0 | 0 | 0 | 1469Mís0000002577 | 1.825 | 1.825 | 29.465 | 16.508 | 8.3 | 6.479 | 6.15 | 3.37 | 0.15 | URGENT
1.26b | Půdorys 1.NP | SPRCHA MUŽI | 1.NP | P02 | keramická dlažba | TVO, T03 | VSO, KO | 0 | 0 | 0 | 0 | 1469Mís0000003049 | 1.73 | 1.73 | 19.933 | 19.933 | 5.95 | 5.796 | 5.571 | 3.22 | 0.1 | URGENT
1.32 | Půdorys 1.NP | ROZVODNA SLBP | 1.NP | P02 | keramická dlažba | TVO, T03 | VSO, KO | 0 | 0 | 0 | 0 | 1469Mís0000003116 | 6.673 | 6.672 | 38.223 | 38.225 | 11.41 | 22.352 | 21.552 | 3.23 | 0.1 | URGENT

# IfcBeam (9)
Name | In | Material = Materiál | Kód prvku | Práce | Text1 | Označení | Podlaží | Allright_Stavebni_dil_ID | Jednotka | Název_objektu | Status | LoadBearing | Height (m) | Width (m) | CrossSectionArea (m2) | GrossVolume (m3) | Length (m)
%K0PY1a | Půdorys 1.PP | PY1a - NEP 100-1250 | PK00.02.0001 | Zednické práce | Překlad pórobetonový | %K0PY1a | 1.PP | 1364Přk0798524589 | Kus | Překlad | NEW | yes | 0.249 | 0.1 | 0.025 | 0.031 | 1.25 | NEMSOK - Statická funkce: Ano
%K0PY3e | Půdorys 1.NP | PY3e - NOP 250-1750 | PK00.03.0001 | Zednické práce | %K0KPP3 | %K0PY3e | 1.NP | 1464Přk1096229580 | Kus | Překlad | NEW | no | 0.249 | 0.25 | 0.062 | 0.109 | 1.75
%K0PY4e | Půdorys 1.NP | PY4e - NOP 250-2000 | PK00.03.0004 | Zednické práce | %K0KPP1 | %K0PY4e | 1.NP | 1464Přk1096229727 | Kus | Překlad | NEW | no | 0.249 | 0.25 | 0.062 | 0.125 | 2
%K0PY3e | Půdorys 1.NP | PY3e - NOP 250-1750 | PK00.03.0003 | Zednické práce | %K0KPP3 | %K0PY3e | 1.NP | 1464Přk1096229664 | Kus | Překlad | NEW | no | 0.249 | 0.25 | 0.062 | 0.109 | 1.75
%K0PY3e | Půdorys 1.NP | PY3e - NOP 250-1750 | PK00.03.0002 | Zednické práce | %K0KPP3 | %K0PY3e | 1.NP | 1464Přk1096229639 | Kus | Překlad | NEW | no | 0.249 | 0.25 | 0.062 | 0.109 | 1.75
%K0PY3f | Půdorys 1.NP | PY3f - NOP 300-1750 | PK00.03.0005 | Zednické práce | %K0KPP3 | %K0PY3f | 1.NP | 1464Přk1096229755 | Kus | Překlad | NEW | no | 0.249 | 0.3 | 0.075 | 0.131 | 1.75
 | Půdorys 1.NP | ZELEZOBETONOVÁ KCE | TM02.03.0001 |  |  |  | 1.NP | 1464Nos1096173839 | m3 | Nosník | NEW |  | 0.12 | 0.3 | 0.036 | 0.248 | 6.9 | NEMSOK - Statická funkce: Ano; 2D interakce: yes; Třída pevnosti ocele: B500B; Stupeň vyztužení: 180; Požární odolnost: REW 45DP1; Třída pevnosti betonu: C25/30-XC1; Krytí výztuže: 25mm; Qto_BeamBaseQuantities - NetVolume: 0.248 m3; OuterSurfaceArea: 5.868 m2
 | Půdorys 5.NP |  |  |  |  |  |  | 1852Nos0000002963 | m3 | Nosník | EXISTING |  | 0.5 | 0.3 | 0.15 | 0.075 | 0.5 | NEMSOK - 2D interakce: yes; Qto_BeamBaseQuantities - NetVolume: 0.06 m3; OuterSurfaceArea: 1.56 m2
 | Půdorys 5.NP |  |  |  |  |  |  | 1852Nos0000002933 | m3 | Nosník | EXISTING |  | 0.5 | 0.3 | 0.15 | 0.525 | 3.5 | NEMSOK - 2D interakce: yes; Qto_BeamBaseQuantities - NetVolume: 0.51 m3; OuterSurfaceArea: 6.36 m2

# IfcBuildingElementPart (10)
In: Půdorys 2.NP
Name | Material
 | II.S2 - KAČÍREK
5 x  | ASFALTOVÁ HYDROIZOLACE
4 x  | KAČÍREK

# IfcBuildingElementProxy (404)
Name | In | Material | Práce | V6 (m) = V7 (m) = V8 (m) = V9 | Označení | Materiál | Allright_Stavebni_dil_ID | Jednotka | Název_objektu | NetSurfaceArea = NetVolume
Parapet vnější | Půdorys 1.NP | PLECH | Klempířské práce | 0 | Parapet vnější | PLECH | 1402Obj0798449424 | m | Parapet - objekt+SmartPart | 1 | NEMSOK - Absolutní_výška: 0.03 m; Tloušťka: 0.2 m; Výška: 0.005 m; Objem: 0.002292; Plocha: 0.4224; Poloha (vnitřní/venkovní): 1
 | Půdorys 1.NP | MINERÁLNÍ VATA | Zateplovací systémy |  |  | MINERÁLNÍ VATA | 1402Zas0798449430 | m2 | Zaslepení | 1
Parapet vnější | Půdorys 1.NP | PLECH | Klempířské práce | 0 | Parapet vnější | PLECH | 1402Obj0798449147 | m | Parapet - objekt+SmartPart | 1 | NEMSOK - Absolutní_výška: 0.03 m; Tloušťka: 0.2 m; Výška: 0.005 m; Objem: 0.002292; Plocha: 0.4224; Poloha (vnitřní/venkovní): 1
 | Půdorys 1.NP | MINERÁLNÍ VATA | Zateplovací systémy |  |  | MINERÁLNÍ VATA | 1402Zas0798449153 | m2 | Zaslepení | 1
Parapet vnější | Půdorys 1.NP | PLECH | Klempířské práce | 0 | Parapet vnější | PLECH | 1402Obj0798449180 | m | Parapet - objekt+SmartPart | 1 | NEMSOK - Absolutní_výška: 0.03 m; Tloušťka: 0.2 m; Výška: 0.005 m; Objem: 0.002292; Plocha: 0.4224; Poloha (vnitřní/venkovní): 1
 | Půdorys 1.NP | MINERÁLNÍ VATA | Zateplovací systémy |  |  | MINERÁLNÍ VATA | 1402Zas0798449186 | m2 | Zaslepení | 1
Parapet vnější | Půdorys 1.NP | PLECH | Klempířské práce | 0 | Parapet vnější | PLECH | 1402Obj0798449213 | m | Parapet - objekt+SmartPart | 1 | NEMSOK - Absolutní_výška: 0.03 m; Tloušťka: 0.2 m; Výška: 0.005 m; Objem: 0.002292; Plocha: 0.4224; Poloha (vnitřní/venkovní): 1
 | Půdorys 1.NP | MINERÁLNÍ VATA | Zateplovací systémy |  |  | MINERÁLNÍ VATA | 1402Zas0798449219 | m2 | Zaslepení | 1
Parapet vnější | Půdorys 1.NP | PLECH | Klempířské práce | 0 | Parapet vnější | PLECH | 1402Obj0798449114 | m | Parapet - objekt+SmartPart | 1 | NEMSOK - Absolutní_výška: 0.03 m; Tloušťka: 0.2 m; Výška: 0.005 m; Objem: 0.002292; Plocha: 0.4224; Poloha (vnitřní/venkovní): 1
 | Půdorys 1.NP | MINERÁLNÍ VATA | Zateplovací systémy |  |  | MINERÁLNÍ VATA | 1402Zas0798449120 | m2 | Zaslepení | 1
Parapet vnější | Půdorys 1.NP | PLECH | Klempířské práce | 0 | Parapet vnější | PLECH | 1402Obj0798449081 | m | Parapet - objekt+SmartPart | 1 | NEMSOK - Absolutní_výška: 0.03 m; Tloušťka: 0.2 m; Výška: 0.005 m; Objem: 0.002292; Plocha: 0.4224; Poloha (vnitřní/venkovní): 1
 | Půdorys 1.NP | MINERÁLNÍ VATA | Zateplovací systémy |  |  | MINERÁLNÍ VATA | 1402Zas0798449087 | m2 | Zaslepení | 1
Parapet vnější | Půdorys 1.NP | PLECH | Klempířské práce | 0 | Parapet vnější | PLECH | 1402Obj0798449048 | m | Parapet - objekt+SmartPart | 1 | NEMSOK - Absolutní_výška: 0.03 m; Tloušťka: 0.2 m; Výška: 0.005 m; Objem: 0.002292; Plocha: 0.4224; Poloha (vnitřní/venkovní): 1
 | Půdorys 1.NP | MINERÁLNÍ VATA | Zateplovací systémy |  |  | MINERÁLNÍ VATA | 1402Zas0798449054 | m2 | Zaslepení | 1
Parapet vnější | Půdorys 1.NP | PLECH | Klempířské práce | 0 | Parapet vnější | PLECH | 1402Obj0798449015 | m | Parapet - objekt+SmartPart | 1 | NEMSOK - Absolutní_výška: 0.03 m; Tloušťka: 0.2 m; Výška: 0.005 m; Objem: 0.002292; Plocha: 0.4224; Poloha (vnitřní/venkovní): 1
 | Půdorys 1.NP | MINERÁLNÍ VATA | Zateplovací systémy |  |  | MINERÁLNÍ VATA | 1402Zas0798449021 | m2 | Zaslepení | 1
Parapet vnější | Půdorys 1.NP | PLECH | Klempířské práce | 0 | Parapet vnější | PLECH | 1402Obj0798448982 | m | Parapet - objekt+SmartPart | 1 | NEMSOK - Absolutní_výška: 0.03 m; Tloušťka: 0.2 m; Výška: 0.005 m; Objem: 0.002292; Plocha: 0.4224; Poloha (vnitřní/venkovní): 1
 | Půdorys 1.NP | MINERÁLNÍ VATA | Zateplovací systémy |  |  | MINERÁLNÍ VATA | 1402Zas0798448988 | m2 | Zaslepení | 1
Parapet vnější | Půdorys 1.NP | PLECH | Klempířské práce | 0 | Parapet vnější | PLECH | 1402Obj0798448951 | m | Parapet - objekt+SmartPart | 1 | NEMSOK - Absolutní_výška: 0.03 m; Tloušťka: 0.2 m; Výška: 0.005 m; Objem: 0.002292; Plocha: 0.4224; Poloha (vnitřní/venkovní): 1
 | Půdorys 1.NP | MINERÁLNÍ VATA | Zateplovací systémy |  |  | MINERÁLNÍ VATA | 1402Zas0798448954 | m2 | Zaslepení | 1
Parapet vnější | Půdorys 1.NP | PLECH | Klempířské práce | 0 | Parapet vnější | PLECH | 1402Obj0798438687 | m | Parapet - objekt+SmartPart | 1 | NEMSOK - Absolutní_výška: 0.03 m; Tloušťka: 0.2 m; Výška: 0.005 m; Objem: 0.002292; Plocha: 0.4224; Poloha (vnitřní/venkovní): 1
 | Půdorys 1.NP | MINERÁLNÍ VATA | Zateplovací systémy |  |  | MINERÁLNÍ VATA | 1402Zas0798438690 | m2 | Zaslepení | 1
 | Půdorys 1.NP | DVEŘNÍ POHON |  |  |  | DVEŘNÍ POHON | 1402ExE0798458265 | m3 | Rozšířený element | 1
 | Půdorys 1.NP | DVEŘNÍ POHON |  |  |  | DVEŘNÍ POHON | 1402ExE0798458678 | m3 | Rozšířený element | 1
 | Půdorys 1.NP | DVEŘNÍ POHON |  |  |  | DVEŘNÍ POHON | 1402ExE0798458679 | m3 | Rozšířený element | 1
 | Půdorys 1.NP | DVEŘNÍ POHON |  |  |  | DVEŘNÍ POHON | 1402ExE0798460021 | m3 | Rozšířený element | 1
Parapet vnější | Půdorys 1.NP | PLECH | Klempířské práce | 0 | Parapet vnější | PLECH | 1402Obj0798462557 | m | Parapet - objekt+SmartPart | 1 | NEMSOK - Absolutní_výška: 0.03 m; Tloušťka: 0.2 m; Výška: 0.005 m; Objem: 0.0010995; Plocha: 0.2064; Poloha (vnitřní/venkovní): 1
 | Půdorys 1.NP | MINERÁLNÍ VATA | Zateplovací systémy |  |  | MINERÁLNÍ VATA | 1402Zas0798462574 | m2 | Zaslepení | 1
Parapet vnější | Půdorys 1.NP | PLECH | Klempířské práce | 0 | Parapet vnější | PLECH | 1402Obj0798462638 | m | Parapet - objekt+SmartPart | 1 | NEMSOK - Absolutní_výška: 0.03 m; Tloušťka: 0.2 m; Výška: 0.005 m; Objem: 0.0010995; Plocha: 0.2064; Poloha (vnitřní/venkovní): 1
 | Půdorys 1.NP | MINERÁLNÍ VATA | Zateplovací systémy |  |  | MINERÁLNÍ VATA | 1402Zas0798462632 | m2 | Zaslepení | 1
Parapet vnější | Půdorys 1.NP | PLECH | Klempířské práce | 0 | Parapet vnější | PLECH | 1402Obj0798462659 | m | Parapet - objekt+SmartPart | 1 | NEMSOK - Absolutní_výška: 0.03 m; Tloušťka: 0.2 m; Výška: 0.005 m; Objem: 0.0010995; Plocha: 0.2064; Poloha (vnitřní/venkovní): 1
 | Půdorys 1.NP | MINERÁLNÍ VATA | Zateplovací systémy |  |  | MINERÁLNÍ VATA | 1402Zas0798462662 | m2 | Zaslepení | 1
Parapet vnější | Půdorys 1.NP | PLECH | Klempířské práce | 0 | Parapet vnější | PLECH | 1402Obj0798462692 | m | Parapet - objekt+SmartPart | 1 | NEMSOK - Absolutní_výška: 0.03 m; Tloušťka: 0.2 m; Výška: 0.005 m; Objem: 0.0010995; Plocha: 0.2064; Poloha (vnitřní/venkovní): 1
 | Půdorys 1.NP | MINERÁLNÍ VATA | Zateplovací systémy |  |  | MINERÁLNÍ VATA | 1402Zas0798462684 | m2 | Zaslepení | 1
Parapet vnější | Půdorys 1.NP | PLECH | Klempířské práce | 0 | Parapet vnější | PLECH | 1402Obj0798439870 | m | Parapet - objekt+SmartPart | 1 | NEMSOK - Absolutní_výška: 0.03 m; Tloušťka: 0.2 m; Výška: 0.005 m; Objem: 0.000702; Plocha: 0.1344; Poloha (vnitřní/venkovní): 1
 | Půdorys 1.NP | MINERÁLNÍ VATA | Zateplovací systémy |  |  | MINERÁLNÍ VATA | 1402Zas0798439854 | m2 | Zaslepení | 1
 | Půdorys 1.NP | DVEŘNÍ POHON |  |  |  | DVEŘNÍ POHON | 1402ExE0798451401 | m3 | Rozšířený element | 1
 | Půdorys 1.NP | DVEŘNÍ POHON |  |  |  | DVEŘNÍ POHON | 1402ExE0798453474 | m3 | Rozšířený element | 1
 | Půdorys 1.NP | DVEŘNÍ POHON |  |  |  | DVEŘNÍ POHON | 1402ExE0798456853 | m3 | Rozšířený element | 1
Parapet vnější | Půdorys 1.NP | PLECH | Klempířské práce | 0 | Parapet vnější | PLECH | 1402Obj0798460814 | m | Parapet - objekt+SmartPart | 1 | NEMSOK - Absolutní_výška: 0.03 m; Tloušťka: 0.2 m; Výška: 0.005 m; Objem: 0.002292; Plocha: 0.4224; Poloha (vnitřní/venkovní): 1
 | Půdorys 1.NP | MINERÁLNÍ VATA | Zateplovací systémy |  |  | MINERÁLNÍ VATA | 1402Zas0798460830 | m2 | Zaslepení | 1
Parapet vnější | Půdorys 1.NP | PLECH | Klempířské práce | 0 | Parapet vnější | PLECH | 1402Obj0798460813 | m | Parapet - objekt+SmartPart | 1 | NEMSOK - Absolutní_výška: 0.03 m; Tloušťka: 0.2 m; Výška: 0.005 m; Objem: 0.002292; Plocha: 0.4224; Poloha (vnitřní/venkovní): 1
 | Půdorys 1.NP | MINERÁLNÍ VATA | Zateplovací systémy |  |  | MINERÁLNÍ VATA | 1402Zas0798460833 | m2 | Zaslepení | 1
Parapet vnější | Půdorys 1.NP | PLECH | Klempířské práce | 0 | Parapet vnější | PLECH | 1402Obj0798460812 | m | Parapet - objekt+SmartPart | 1 | NEMSOK - Absolutní_výška: 0.03 m; Tloušťka: 0.2 m; Výška: 0.005 m; Objem: 0.002292; Plocha: 0.4224; Poloha (vnitřní/venkovní): 1
 | Půdorys 1.NP | MINERÁLNÍ VATA | Zateplovací systémy |  |  | MINERÁLNÍ VATA | 1402Zas0798460836 | m2 | Zaslepení | 1
Parapet vnější | Půdorys 1.NP | PLECH | Klempířské práce | 0 | Parapet vnější | PLECH | 1402Obj0798460811 | m | Parapet - objekt+SmartPart | 1 | NEMSOK - Absolutní_výška: 0.03 m; Tloušťka: 0.2 m; Výška: 0.005 m; Objem: 0.002292; Plocha: 0.4224; Poloha (vnitřní/venkovní): 1
 | Půdorys 1.NP | MINERÁLNÍ VATA | Zateplovací systémy |  |  | MINERÁLNÍ VATA | 1402Zas0798460839 | m2 | Zaslepení | 1
Parapet vnější | Půdorys 1.NP | PLECH | Klempířské práce | 0 | Parapet vnější | PLECH | 1402Obj0798460810 | m | Parapet - objekt+SmartPart | 1 | NEMSOK - Absolutní_výška: 0.03 m; Tloušťka: 0.2 m; Výška: 0.005 m; Objem: 0.002292; Plocha: 0.4224; Poloha (vnitřní/venkovní): 1
 | Půdorys 1.NP | MINERÁLNÍ VATA | Zateplovací systémy |  |  | MINERÁLNÍ VATA | 1402Zas0798460842 | m2 | Zaslepení | 1
 | Půdorys 2.NP | MINERÁLNÍ VATA | Zateplovací systémy |  |  | MINERÁLNÍ VATA | 1502Zas0000004161 | m2 | Zaslepení | 1
 | Půdorys 2.NP | MINERÁLNÍ VATA | Zateplovací systémy |  |  | MINERÁLNÍ VATA | 1502Zas0000004199 | m2 | Zaslepení | 1
 | Půdorys 2.NP | MINERÁLNÍ VATA | Zateplovací systémy |  |  | MINERÁLNÍ VATA | 1502Zas0000004232 | m2 | Zaslepení | 1
Parapet vnější | Půdorys 2.NP | PLECH | Klempířské práce | 0 | Parapet vnější | PLECH | 1502Obj0000004625 | m | Parapet - objekt+SmartPart | 1 | NEMSOK - Absolutní_výška: 0.03 m; Tloušťka: 0.2 m; Výška: 0.005 m; Poloha (vnitřní/venkovní): 1
 | Půdorys 2.NP | MINERÁLNÍ VATA | Zateplovací systémy |  |  | MINERÁLNÍ VATA | 1502Zas0000004621 | m2 | Zaslepení | 1
Parapet vnější | Půdorys 2.NP | PLECH | Klempířské práce | 0 | Parapet vnější | PLECH | 1502Obj0000004014 | m | Parapet - objekt+SmartPart | 1 | NEMSOK - Absolutní_výška: 0.03 m; Tloušťka: 0.2 m; Výška: 0.005 m; Poloha (vnitřní/venkovní): 1
 | Půdorys 2.NP | MINERÁLNÍ VATA | Zateplovací systémy |  |  | MINERÁLNÍ VATA | 1502Zas0000004000 | m2 | Zaslepení | 1
 | Půdorys 2.NP | MINERÁLNÍ VATA | Zateplovací systémy |  |  | MINERÁLNÍ VATA | 1502Zas0000005979 | m2 | Zaslepení | 1
Parapet vnější | Půdorys 2.NP | PLECH | Klempířské práce | 0 | Parapet vnější | PLECH | 1502Obj0000004402 | m | Parapet - objekt+SmartPart | 1 | NEMSOK - Absolutní_výška: 0.03 m; Tloušťka: 0.2 m; Výška: 0.005 m; Poloha (vnitřní/venkovní): 1
 | Půdorys 2.NP | MINERÁLNÍ VATA | Zateplovací systémy |  |  | MINERÁLNÍ VATA | 1502Zas0000004407 | m2 | Zaslepení | 1
Parapet vnější | Půdorys 2.NP | PLECH | Klempířské práce | 0 | Parapet vnější | PLECH | 1502Obj0000004522 | m | Parapet - objekt+SmartPart | 1 | NEMSOK - Absolutní_výška: 0.03 m; Tloušťka: 0.2 m; Výška: 0.005 m; Poloha (vnitřní/venkovní): 1
 | Půdorys 2.NP | MINERÁLNÍ VATA | Zateplovací systémy |  |  | MINERÁLNÍ VATA | 1502Zas0000004518 | m2 | Zaslepení | 1
Parapet vnější | Půdorys 2.NP | HLINÍKOVÝ PLECH ELOXOVANÝ | Klempířské práce | 0 | Parapet vnější | HLINÍKOVÝ PLECH ELOXOVANÝ | 1514Obj0000000031 | m | II.K1 | 1 | NEMSOK - Absolutní_výška: 0.03 m; Tloušťka: 0.2 m; Výška: 0.005 m; Poloha (vnitřní/venkovní): 1; Kód prvku: KV01.04.0003; Podlaží: 2.NP; Rozvinutá šířka: 0.32 m; Pset_BuildingElementProxyCommon - Status: NEW
Parapet vnější | Půdorys 2.NP | HLINÍKOVÝ PLECH ELOXOVANÝ | Klempířské práce | 0 | Parapet vnější | HLINÍKOVÝ PLECH ELOXOVANÝ | 1514Obj0000000032 | m | II.K1 | 1 | NEMSOK - Absolutní_výška: 0.03 m; Tloušťka: 0.2 m; Výška: 0.005 m; Poloha (vnitřní/venkovní): 1; Kód prvku: KV01.04.0004; Podlaží: 2.NP; Rozvinutá šířka: 0.32 m; Pset_BuildingElementProxyCommon - Status: NEW
Parapet vnější | Půdorys 2.NP | HLINÍKOVÝ PLECH ELOXOVANÝ | Klempířské práce | 0 | Parapet vnější | HLINÍKOVÝ PLECH ELOXOVANÝ | 1514Obj0000000034 | m | Parapet - objekt+SmartPart | 1 | NEMSOK - Absolutní_výška: 0.03 m; Tloušťka: 0.2 m; Výška: 0.005 m; Poloha (vnitřní/venkovní): 1; Kód prvku: KV01.04.0005; Podlaží: 2.NP; Rozvinutá šířka: 0.32 m; Pset_BuildingElementProxyCommon - Status: NEW
Parapet vnější | Půdorys 2.NP | HLINÍKOVÝ PLECH ELOXOVANÝ | Klempířské práce | 0 | Parapet vnější | HLINÍKOVÝ PLECH ELOXOVANÝ | 1514Obj0000000030 | m | II.K1 | 1 | NEMSOK - Absolutní_výška: 0.03 m; Tloušťka: 0.2 m; Výška: 0.005 m; Poloha (vnitřní/venkovní): 1; Kód prvku: KV01.04.0002; Podlaží: 2.NP; Rozvinutá šířka: 0.32 m; Pset_BuildingElementProxyCommon - Status: NEW
mz04 | Výkopy | HEB 100 |  | 0 | mz04 | HEB 100 | 0851Sma0000011987 | Kus | SmartPart | 1 | NEMSOK - Kód prvku: PP03.01.0004; Verze programu: 1.0; Plugin_Bezeichnung: MainObject; Plugin_Objektname: SmartPartCompressed; Verze: 1.0
mz08 | Výkopy | HEB 100 |  | 0 | mz08 | HEB 100 | 0851Sma0000011971 | Kus | SmartPart | 1 | NEMSOK - Kód prvku: PP03.01.0008; Verze programu: 1.0; Plugin_Bezeichnung: MainObject; Plugin_Objektname: SmartPartCompressed; Verze: 1.0
mz07 | Výkopy | HEB 100 |  | 0 | mz07 | HEB 100 | 0851Sma0000011975 | Kus | SmartPart | 1 | NEMSOK - Kód prvku: PP03.01.0007; Verze programu: 1.0; Plugin_Bezeichnung: MainObject; Plugin_Objektname: SmartPartCompressed; Verze: 1.0
mz06 | Výkopy | HEB 100 |  | 0 | mz06 | HEB 100 | 0851Sma0000011979 | Kus | SmartPart | 1 | NEMSOK - Kód prvku: PP03.01.0006; Verze programu: 1.0; Plugin_Bezeichnung: MainObject; Plugin_Objektname: SmartPartCompressed; Verze: 1.0
mz05 | Výkopy | HEB 100 |  | 0 | mz05 | HEB 100 | 0851Sma0000011983 | Kus | SmartPart | 1 | NEMSOK - Kód prvku: PP03.01.0005; Verze programu: 1.0; Plugin_Bezeichnung: MainObject; Plugin_Objektname: SmartPartCompressed; Verze: 1.0
mz12 | Výkopy | HEB 100 |  | 0 | mz12 | HEB 100 | 0851Sma0000011955 | Kus | SmartPart | 1 | NEMSOK - Kód prvku: PP03.01.0012; Verze programu: 1.0; Plugin_Bezeichnung: MainObject; Plugin_Objektname: SmartPartCompressed; Verze: 1.0
mz10 | Výkopy | HEB 100 |  | 0 | mz10 | HEB 100 | 0851Sma0000011963 | Kus | SmartPart | 1 | NEMSOK - Kód prvku: PP03.01.0010; Verze programu: 1.0; Plugin_Bezeichnung: MainObject; Plugin_Objektname: SmartPartCompressed; Verze: 1.0
mz09 | Výkopy | HEB 100 |  | 0 | mz09 | HEB 100 | 0851Sma0000011967 | Kus | SmartPart | 1 | NEMSOK - Kód prvku: PP03.01.0009; Verze programu: 1.0; Plugin_Bezeichnung: MainObject; Plugin_Objektname: SmartPartCompressed; Verze: 1.0
mz23 | Výkopy | HEB 100 |  | 0 | mz23 | HEB 100 | 0851Sma0000011630 | Kus | SmartPart | 1 | NEMSOK - Kód prvku: PP03.01.0023; Verze programu: 1.0; Plugin_Bezeichnung: MainObject; Plugin_Objektname: SmartPartCompressed; Verze: 1.0
mz22 | Výkopy | HEB 100 |  | 0 | mz22 | HEB 100 | 0851Sma0000011629 | Kus | SmartPart | 1 | NEMSOK - Kód prvku: PP03.01.0022; Verze programu: 1.0; Plugin_Bezeichnung: MainObject; Plugin_Objektname: SmartPartCompressed; Verze: 1.0
mz21 | Výkopy | HEB 100 |  | 0 | mz21 | HEB 100 | 0851Sma0000011628 | Kus | SmartPart | 1 | NEMSOK - Kód prvku: PP03.01.0021; Verze programu: 1.0; Plugin_Bezeichnung: MainObject; Plugin_Objektname: SmartPartCompressed; Verze: 1.0
mz20 | Výkopy | HEB 100 |  | 0 | mz20 | HEB 100 | 0851Sma0000011627 | Kus | SmartPart | 1 | NEMSOK - Kód prvku: PP03.01.0020; Verze programu: 1.0; Plugin_Bezeichnung: MainObject; Plugin_Objektname: SmartPartCompressed; Verze: 1.0
mz19 | Výkopy | HEB 100 |  | 0 | mz19 | HEB 100 | 0851Sma0000011626 | Kus | SmartPart | 1 | NEMSOK - Kód prvku: PP03.01.0019; Verze programu: 1.0; Plugin_Bezeichnung: MainObject; Plugin_Objektname: SmartPartCompressed; Verze: 1.0
mz18 | Výkopy | HEB 100 |  | 0 | mz18 | HEB 100 | 0851Sma0000011625 | Kus | SmartPart | 1 | NEMSOK - Kód prvku: PP03.01.0018; Verze programu: 1.0; Plugin_Bezeichnung: MainObject; Plugin_Objektname: SmartPartCompressed; Verze: 1.0
mz17 | Výkopy | HEB 100 |  | 0 | mz17 | HEB 100 | 0851Sma0000011624 | Kus | SmartPart | 1 | NEMSOK - Kód prvku: PP03.01.0017; Verze programu: 1.0; Plugin_Bezeichnung: MainObject; Plugin_Objektname: SmartPartCompressed; Verze: 1.0
mz16 | Výkopy | HEB 100 |  | 0 | mz16 | HEB 100 | 0851Sma0000011623 | Kus | SmartPart | 1 | NEMSOK - Kód prvku: PP03.01.0016; Verze programu: 1.0; Plugin_Bezeichnung: MainObject; Plugin_Objektname: SmartPartCompressed; Verze: 1.0
mz15 | Výkopy | HEB 100 |  | 0 | mz15 | HEB 100 | 0851Sma0000011622 | Kus | SmartPart | 1 | NEMSOK - Kód prvku: PP03.01.0015; Verze programu: 1.0; Plugin_Bezeichnung: MainObject; Plugin_Objektname: SmartPartCompressed; Verze: 1.0
mz14 | Výkopy | HEB 100 |  | 0 | mz14 | HEB 100 | 0851Sma0000011608 | Kus | SmartPart | 1 | NEMSOK - Kód prvku: PP03.01.0014; Verze programu: 1.0; Plugin_Bezeichnung: MainObject; Plugin_Objektname: SmartPartCompressed; Verze: 1.0
mz11 | Výkopy | HEB 100 |  | 0 | mz11 | HEB 100 | 0851Sma0000011959 | Kus | SmartPart | 1 | NEMSOK - Kód prvku: PP03.01.0011; Verze programu: 1.0; Plugin_Bezeichnung: MainObject; Plugin_Objektname: SmartPartCompressed; Verze: 1.0
mz01 | Výkopy | HEB 100 |  | 0 | mz01 | HEB 100 | 0851Sma0000011999 | Kus | SmartPart | 1 | NEMSOK - Kód prvku: PP03.01.0001; Verze programu: 1.0; Plugin_Bezeichnung: MainObject; Plugin_Objektname: SmartPartCompressed; Verze: 1.0
mz02 | Výkopy | HEB 100 |  | 0 | mz02 | HEB 100 | 0851Sma0000011995 | Kus | SmartPart | 1 | NEMSOK - Kód prvku: PP03.01.0002; Verze programu: 1.0; Plugin_Bezeichnung: MainObject; Plugin_Objektname: SmartPartCompressed; Verze: 1.0
mz03 | Výkopy | HEB 100 |  | 0 | mz03 | HEB 100 | 0851Sma0000011991 | Kus | SmartPart | 1 | NEMSOK - Kód prvku: PP03.01.0003; Verze programu: 1.0; Plugin_Bezeichnung: MainObject; Plugin_Objektname: SmartPartCompressed; Verze: 1.0
mz13 | Výkopy | HEB 100 |  | 0 | mz13 | HEB 100 | 0851Sma0000012070 | Kus | SmartPart | 1 | NEMSOK - Kód prvku: PP03.01.0013; Verze programu: 1.0; Plugin_Bezeichnung: MainObject; Plugin_Objektname: SmartPartCompressed; Verze: 1.0
Ocelový profil | Půdorys 1.PP | U 140 |  | 0 | Ocelový profil | U 140 | 1352Sma0000001552 | Kus | SmartPart | 1 | NEMSOK - Verze programu: 1.0; Plugin_Bezeichnung: MainObject; Plugin_Objektname: SmartPartCompressed; Verze: 1.0; Dolní_hrana: 0 m; Horní_hrana: 0 m
Ocelový profil | Půdorys 1.PP | U 140 |  | 0 | Ocelový profil | U 140 | 1352Sma0000001553 | Kus | SmartPart | 1 | NEMSOK - Verze programu: 1.0; Plugin_Bezeichnung: MainObject; Plugin_Objektname: SmartPartCompressed; Verze: 1.0; Dolní_hrana: 0 m; Horní_hrana: 0 m
Parapet vnější | Půdorys 1.PP | PLECH | Klempířské práce | 0 | Parapet vnější | PLECH | 1352Obj0798472356 | m | Parapet - objekt+SmartPart | 1 | NEMSOK - Absolutní_výška: 0.03 m; Tloušťka: 0.2 m; Výška: 0.005 m; Objem: 0.001731; Plocha: 0.3157; Poloha (vnitřní/venkovní): 1; Pset_BuildingElementProxyCommon - Status: DEMOLISH
Parapet vnější | Půdorys 1.PP | PLECH | Klempířské práce | 0 | Parapet vnější | PLECH | 1352Obj0798472442 | m | Parapet - objekt+SmartPart | 1 | NEMSOK - Absolutní_výška: 0.03 m; Tloušťka: 0.2 m; Výška: 0.005 m; Objem: 0.001731; Plocha: 0.3157; Poloha (vnitřní/venkovní): 1; Pset_BuildingElementProxyCommon - Status: DEMOLISH
Parapet vnější | Půdorys 1.PP | PLECH | Klempířské práce | 0 | Parapet vnější | PLECH | 1352Obj0798472466 | m | Parapet - objekt+SmartPart | 1 | NEMSOK - Absolutní_výška: 0.03 m; Tloušťka: 0.2 m; Výška: 0.005 m; Objem: 0.001731; Plocha: 0.3157; Poloha (vnitřní/venkovní): 1; Pset_BuildingElementProxyCommon - Status: DEMOLISH
I.Z6 | Půdorys 1.PP | REVIZNÍ DVÍŘKA |  | 0 | I.Z6 | REVIZNÍ DVÍŘKA | 1364Obj0000002217 | Kus | Objekt | 1 | NEMSOK - Kód prvku: ZV00.02.6001; Verze programu: 2.2; Plugin_Bezeichnung: MainObject; Plugin_Objektname: SmartPartCompressed; Verze: 3.0; Jednotková_cena: 0; Uvažované procento prosklení: 100; Plocha_skla: 0; Výška_vnějšího_parapetu: 0 m; Výška_vnitřního_parapetu: 0 m; Odstup_od_otvoru_dole: 0 m; Odstup_od_otvoru_nahoře: 0 m; Odstup_od_otvoru_vlevo: 0 m; Odstup_od_otvoru_vpravo: 0 m; Tloušťka_zárubně/rámu_dole: 0.02 m; Tloušťka_zárubně/rámu_vlevo: 0.02 m; Tloušťka_zárubně/rámu_vpravo: 0.02 m; Tloušťka_zárubně/rámu_nahoře: 0.02 m; Ochrana proti kouři: no; Nouzový východ: no; Bezpečnostní třída: SA; Zárubeň/Rám_Typ: Ocelový rám; Zárubeň/Rám_Materiál: Ocelová; Zárubeň/Rám_Povrch: Bílý lak; Křídlo_Materiál: Ocelové; Křídlo_Povrch_Int.: Bílý lak; Křídlo_Povrch_Ext.: Bílý lak; Kování_Klika_Ext.: není; Kování_Zámek: není; Pset_BuildingElementProxyCommon - ThermalTransmittance: 0 W/K/m2
Parapet vnější | Půdorys 1.PP | HLINÍKOVÝ PLECH ELOXOVANÝ | Klempířské práce | 0 | Parapet vnější | HLINÍKOVÝ PLECH ELOXOVANÝ | 1364Obj0798521234 | m | Parapet - objekt+SmartPart | 1 | NEMSOK - Absolutní_výška: 0.03 m; Tloušťka: 0.118 m; Výška: 0.005 m; Poloha (vnitřní/venkovní): 1; Kód prvku: ON04.02.0008; Podlaží: 1.PP; Rozvinutá šířka: 0.24 m; Pset_BuildingElementProxyCommon - Status: NEW
Parapet vnější | Půdorys 1.PP | HLINÍKOVÝ PLECH ELOXOVANÝ | Klempířské práce | 0 | Parapet vnější | HLINÍKOVÝ PLECH ELOXOVANÝ | 1364Obj0798521335 | m | Parapet - objekt+SmartPart | 1 | NEMSOK - Absolutní_výška: 0.03 m; Tloušťka: 0.118 m; Výška: 0.005 m; Poloha (vnitřní/venkovní): 1; Kód prvku: ON04.02.0009; Podlaží: 1.PP; Rozvinutá šířka: 0.24 m; Pset_BuildingElementProxyCommon - Status: NEW
Parapet vnější | Půdorys 1.PP | HLINÍKOVÝ PLECH ELOXOVANÝ | Klempířské práce | 0 | Parapet vnější | HLINÍKOVÝ PLECH ELOXOVANÝ | 1364Obj0798521394 | m | Parapet - objekt+SmartPart | 1 | NEMSOK - Absolutní_výška: 0.03 m; Tloušťka: 0.118 m; Výška: 0.005 m; Poloha (vnitřní/venkovní): 1; Kód prvku: ON04.02.0010; Podlaží: 1.PP; Rozvinutá šířka: 0.24 m; Pset_BuildingElementProxyCommon - Status: NEW
Parapet vnější | Půdorys 1.PP | HLINÍKOVÝ PLECH ELOXOVANÝ | Klempířské práce | 0 | Parapet vnější | HLINÍKOVÝ PLECH ELOXOVANÝ | 1364Obj0798521515 | m | Parapet - objekt+SmartPart | 1 | NEMSOK - Absolutní_výška: 0.03 m; Tloušťka: 0.118 m; Výška: 0.005 m; Poloha (vnitřní/venkovní): 1; Kód prvku: ON04.02.0004; Podlaží: 1.PP; Rozvinutá šířka: 0.24 m; Pset_BuildingElementProxyCommon - Status: NEW
Parapet vnější | Půdorys 1.PP | PLECH | Klempířské práce | 0 | Parapet vnější | PLECH | 1364Obj0798521535 | m | Parapet - objekt+SmartPart | 1 | NEMSOK - Absolutní_výška: 0.03 m; Tloušťka: 0.118 m; Výška: 0.005 m; Poloha (vnitřní/venkovní): 1; Podlaží: 1.PP; Rozvinutá šířka: 0.24 m; Pset_BuildingElementProxyCommon - Status: DEMOLISH
Parapet vnější | Půdorys 1.PP | HLINÍKOVÝ PLECH ELOXOVANÝ | Klempířské práce | 0 | Parapet vnější | HLINÍKOVÝ PLECH ELOXOVANÝ | 1364Obj0798521495 | m | Parapet - objekt+SmartPart | 1 | NEMSOK - Absolutní_výška: 0.03 m; Tloušťka: 0.118 m; Výška: 0.005 m; Poloha (vnitřní/venkovní): 1; Kód prvku: ON04.02.0007; Podlaží: 1.PP; Rozvinutá šířka: 0.24 m; Pset_BuildingElementProxyCommon - Status: NEW
Parapet vnější | Půdorys 1.PP | HLINÍKOVÝ PLECH ELOXOVANÝ | Klempířské práce | 0 | Parapet vnější | HLINÍKOVÝ PLECH ELOXOVANÝ | 1364Obj0798606592 | m | Parapet - objekt+SmartPart | 1 | NEMSOK - Absolutní_výška: 0.03 m; Tloušťka: 0.2 m; Výška: 0.005 m; Poloha (vnitřní/venkovní): 1; Kód prvku: ON04.02.0011; Podlaží: 1.PP; Rozvinutá šířka: 0.32 m; Pset_BuildingElementProxyCommon - Status: NEW
Parapet vnější | Půdorys 1.PP | HLINÍKOVÝ PLECH ELOXOVANÝ | Klempířské práce | 0 | Parapet vnější | HLINÍKOVÝ PLECH ELOXOVANÝ | 1364Obj0798606810 | m | Parapet - objekt+SmartPart | 1 | NEMSOK - Absolutní_výška: 0.03 m; Tloušťka: 0.2 m; Výška: 0.005 m; Poloha (vnitřní/venkovní): 1; Kód prvku: ON04.02.0014; Podlaží: 1.PP; Rozvinutá šířka: 0.32 m; Pset_BuildingElementProxyCommon - Status: NEW
Parapet vnější | Půdorys 1.PP | HLINÍKOVÝ PLECH ELOXOVANÝ | Klempířské práce | 0 | Parapet vnější | HLINÍKOVÝ PLECH ELOXOVANÝ | 1364Obj0798606764 | m | Parapet - objekt+SmartPart | 1 | NEMSOK - Absolutní_výška: 0.03 m; Tloušťka: 0.2 m; Výška: 0.005 m; Poloha (vnitřní/venkovní): 1; Kód prvku: ON04.02.0013; Podlaží: 1.PP; Rozvinutá šířka: 0.32 m; Pset_BuildingElementProxyCommon - Status: NEW
Parapet vnější | Půdorys 1.PP | HLINÍKOVÝ PLECH ELOXOVANÝ | Klempířské práce | 0 | Parapet vnější | HLINÍKOVÝ PLECH ELOXOVANÝ | 1364Obj0798606730 | m | Parapet - objekt+SmartPart | 1 | NEMSOK - Absolutní_výška: 0.03 m; Tloušťka: 0.2 m; Výška: 0.005 m; Poloha (vnitřní/venkovní): 1; Kód prvku: ON04.02.0012; Podlaží: 1.PP; Rozvinutá šířka: 0.32 m; Pset_BuildingElementProxyCommon - Status: NEW
Parapet vnější | Půdorys 1.PP | HLINÍKOVÝ PLECH ELOXOVANÝ | Klempířské práce | 0 | Parapet vnější | HLINÍKOVÝ PLECH ELOXOVANÝ | 1364Obj0798606949 | m | Parapet - objekt+SmartPart | 1 | NEMSOK - Absolutní_výška: 0.03 m; Tloušťka: 0.2 m; Výška: 0.005 m; Poloha (vnitřní/venkovní): 1; Kód prvku: ON04.02.0015; Podlaží: 1.PP; Rozvinutá šířka: 0.32 m; Pset_BuildingElementProxyCommon - Status: NEW
Parapet vnější | Půdorys 1.PP | HLINÍKOVÝ PLECH ELOXOVANÝ | Klempířské práce | 0 | Parapet vnější | HLINÍKOVÝ PLECH ELOXOVANÝ | 1364Obj0798508079 | m | Parapet - objekt+SmartPart | 1 | NEMSOK - Absolutní_výška: 0.03 m; Tloušťka: 0.138 m; Výška: 0.005 m; Objem: 0.0015355; Plocha: 0.27412; Poloha (vnitřní/venkovní): 1; Kód prvku: ON04.02.0005; Podlaží: 1.PP; Rozvinutá šířka: 0.26 m; Pset_BuildingElementProxyCommon - Status: NEW
Parapet vnější | Půdorys 1.PP | HLINÍKOVÝ PLECH ELOXOVANÝ | Klempířské práce | 0 | Parapet vnější | HLINÍKOVÝ PLECH ELOXOVANÝ | 1364Obj0798507947 | m | Parapet - objekt+SmartPart | 1 | NEMSOK - Absolutní_výška: 0.03 m; Tloušťka: 0.138 m; Výška: 0.005 m; Objem: 0.0015355; Plocha: 0.27412; Poloha (vnitřní/venkovní): 1; Kód prvku: ON04.02.0006; Podlaží: 1.PP; Rozvinutá šířka: 0.26 m; Pset_BuildingElementProxyCommon - Status: NEW
Parapet vnější | Půdorys 1.PP | HLINÍKOVÝ PLECH ELOXOVANÝ | Klempířské práce | 0 | Parapet vnější | HLINÍKOVÝ PLECH ELOXOVANÝ | 1364Obj0798607520 | m | Parapet - objekt+SmartPart | 1 | NEMSOK - Absolutní_výška: 0.03 m; Tloušťka: 0.2 m; Výška: 0.005 m; Objem: 0.0012055; Plocha: 0.2256; Poloha (vnitřní/venkovní): 1; Kód prvku: ON04.02.0001; Podlaží: 1.PP; Rozvinutá šířka: 0.32 m; Pset_BuildingElementProxyCommon - Status: NEW
Parapet vnější | Půdorys 1.PP | HLINÍKOVÝ PLECH ELOXOVANÝ | Klempířské práce | 0 | Parapet vnější | HLINÍKOVÝ PLECH ELOXOVANÝ | 1364Obj0798607540 | m | Parapet - objekt+SmartPart | 1 | NEMSOK - Absolutní_výška: 0.03 m; Tloušťka: 0.2 m; Výška: 0.005 m; Objem: 0.0012055; Plocha: 0.2256; Poloha (vnitřní/venkovní): 1; Kód prvku: ON04.02.0002; Podlaží: 1.PP; Rozvinutá šířka: 0.32 m; Pset_BuildingElementProxyCommon - Status: NEW
Parapet vnější | Půdorys 1.PP | HLINÍKOVÝ PLECH ELOXOVANÝ | Klempířské práce | 0 | Parapet vnější | HLINÍKOVÝ PLECH ELOXOVANÝ | 1364Obj0798607560 | m | Parapet - objekt+SmartPart | 1 | NEMSOK - Absolutní_výška: 0.03 m; Tloušťka: 0.2 m; Výška: 0.005 m; Objem: 0.0012055; Plocha: 0.2256; Poloha (vnitřní/venkovní): 1; Kód prvku: ON04.02.0003; Podlaží: 1.PP; Rozvinutá šířka: 0.32 m; Pset_BuildingElementProxyCommon - Status: NEW
MADLO DVEŘNÍ | Půdorys 1.PP |  |  | 0 | MADLO DVEŘNÍ |  | 1364Obj0798526341 | Kus | Objekt | 1 | NEMSOK - Dolní_hrana: 0 m; Horní_hrana: 0 m; Samozavírací: no
MADLO DVEŘNÍ | Půdorys 1.PP |  |  | 0 | MADLO DVEŘNÍ |  | 1364Obj0798526343 | Kus | Objekt | 1 | NEMSOK - Dolní_hrana: 0 m; Horní_hrana: 0 m; Samozavírací: no
MADLO DVEŘNÍ | Půdorys 1.PP |  |  | 0 | MADLO DVEŘNÍ |  | 1364Obj0798526345 | Kus | Objekt | 1 | NEMSOK - Dolní_hrana: 0 m; Horní_hrana: 0 m; Samozavírací: no
MADLO DVEŘNÍ | Půdorys 1.PP |  |  | 0 | MADLO DVEŘNÍ |  | 1364Obj0798526347 | Kus | Objekt | 1 | NEMSOK - Dolní_hrana: 0 m; Horní_hrana: 0 m; Samozavírací: no
MADLO DVEŘNÍ | Půdorys 1.PP |  |  | 0 | MADLO DVEŘNÍ |  | 1364Obj0798526348 | Kus | Objekt | 1 | NEMSOK - Dolní_hrana: 0 m; Horní_hrana: 0 m; Samozavírací: no
MADLO DVEŘNÍ | Půdorys 1.PP |  |  | 0 | MADLO DVEŘNÍ |  | 1364Obj0798526349 | Kus | Objekt | 1 | NEMSOK - Dolní_hrana: 0 m; Horní_hrana: 0 m; Samozavírací: no
MADLO DVEŘNÍ | Půdorys 1.PP |  |  | 0 | MADLO DVEŘNÍ |  | 1364Obj0798526350 | Kus | Objekt | 1 | NEMSOK - Dolní_hrana: 0 m; Horní_hrana: 0 m; Samozavírací: no
MADLO DVEŘNÍ | Půdorys 1.PP |  |  | 0 | MADLO DVEŘNÍ |  | 1364Obj0798526351 | Kus | Objekt | 1 | NEMSOK - Dolní_hrana: 0 m; Horní_hrana: 0 m; Samozavírací: no
MADLO DVEŘNÍ | Půdorys 1.PP |  |  | 0 | MADLO DVEŘNÍ |  | 1364Obj0798526352 | Kus | Objekt | 1 | NEMSOK - Dolní_hrana: 0 m; Horní_hrana: 0 m; Samozavírací: no
MADLO DVEŘNÍ | Půdorys 1.PP |  |  | 0 | MADLO DVEŘNÍ |  | 1364Obj0798526353 | Kus | Objekt | 1 | NEMSOK - Dolní_hrana: 0 m; Horní_hrana: 0 m; Samozavírací: no
MADLO DVEŘNÍ | Půdorys 1.PP |  |  | 0 | MADLO DVEŘNÍ |  | 1364Obj0798527226 | Kus | Objekt | 1 | NEMSOK - Dolní_hrana: 0 m; Horní_hrana: 0 m; Samozavírací: no
I.D016 | Půdorys 1.PP |  |  | 0 | I.D016 |  | 1364Obj0000005237 | Kus | Dveře - objekt+SmartPart | 1 | NEMSOK - Kód prvku: DD01.02.0016; Podlaží: 1.PP; Verze programu: 2.2; Plugin_Bezeichnung: MainObject; Plugin_Objektname: SmartPartCompressed; Verze: 4.0; Jednotková_cena: 0; Uvažované procento prosklení: 100; Plocha_skla: 1.69598; Výška_vnějšího_parapetu: 0 m; Výška_vnitřního_parapetu: 0 m; Odstup_od_otvoru_dole: 0 m; Odstup_od_otvoru_nahoře: 0 m; Odstup_od_otvoru_vlevo: 0 m; Odstup_od_otvoru_vpravo: 0 m; Tloušťka_zárubně/rámu_dole: 0.1 m; Tloušťka_zárubně/rámu_vlevo: 0.05 m; Tloušťka_zárubně/rámu_vpravo: 0.05 m; Tloušťka_zárubně/rámu_nahoře: 0.05 m; Ochrana proti kouři: no; Nouzový východ: no; Bezpečnostní třída: bez; Zárubeň/Rám_Typ: dvoudílná; Zárubeň/Rám_Materiál: Ocelová; Zárubeň/Rám_Povrch: komaxit; Křídlo_Materiál: Dřevěné; Křídlo_Povrch_Int.: HPL laminát; Křídlo_Povrch_Ext.: HPL laminát; Kování_Klika_Ext.: paniková klika; Kování_Zámek: mechanický vložkový; Samozavírací: no; Bezbariérový přístup: no; šířka: 1450; výška: 1970; Funkce (venkovní): Ne; Připojení EZS: Ne; Připojení NN: Ne; Připojení EPS: Ne; Připojení MaR: Ne; Připojení ACS: Ne; Typ dveřní zarážky: Bez; Typ samozavírače: Hřebenový s kluznou lištou + požární konzole; Vzduchová neprůzvučnost: 0; Dveře_Světlá-šířka: 0.9 m; Dveře_Světlá-výška: 0 m; Kování_Klika_Int.: klika; Specifikace: Interiérové dveře dvoukřídlé prosklené; Height: 2.12 m; Length: 1.55 m; Pset_BuildingElementProxyCommon - Status: NEW; ThermalTransmittance: 0 W/K/m2; IsExternal: no; FireRating: EI 30DP3-Sm-C
 | Půdorys 1.PP |  |  | 0 |  |  | 1364Obj0798563470 | Kus | Objekt - stěnová nika | 1 | NEMSOK - Verze programu: 2.2; Plugin_Bezeichnung: MainObject; Plugin_Objektname: SmartPartCompressed; Verze: 3.0; Jednotková_cena: 0; Uvažované procento prosklení: 100; Plocha_skla: 0; Výška_vnějšího_parapetu: 0 m; Výška_vnitřního_parapetu: 0 m; Odstup_od_otvoru_dole: 0 m; Odstup_od_otvoru_nahoře: 0 m; Odstup_od_otvoru_vlevo: 0 m; Odstup_od_otvoru_vpravo: 0 m; Tloušťka_zárubně/rámu_dole: 0.02 m; Tloušťka_zárubně/rámu_vlevo: 0.02 m; Tloušťka_zárubně/rámu_vpravo: 0.02 m; Tloušťka_zárubně/rámu_nahoře: 0.02 m; Ochrana proti kouři: no; Nouzový východ: no; Bezpečnostní třída: bez; Zárubeň/Rám_Typ: Ocelový rám; Zárubeň/Rám_Materiál: Ocelová; Zárubeň/Rám_Povrch: Bílý lak; Křídlo_Materiál: Ocelové; Křídlo_Povrch_Int.: Bílý lak; Křídlo_Povrch_Ext.: Bílý lak; Kování_Klika_Ext.: není; Kování_Zámek: není; Kování_Klika_Int.: Okenní klika; Specifikace: Bemerkung mit max 254Zeichen; Kování_Závěsy: Celoobvodové kování s pětibodovým uzávěrem; Pset_BuildingElementProxyCommon - ThermalTransmittance: 0 W/K/m2
 | Půdorys 1.PP |  |  | 0 |  |  | 1364Obj0798563421 | Kus | Okno - objekt+SmartPart | 1 | NEMSOK - Verze programu: 2.2; Plugin_Bezeichnung: MainObject; Plugin_Objektname: SmartPartCompressed; Verze: 3.0; Jednotková_cena: 0; Uvažované procento prosklení: 100; Plocha_skla: 0; Výška_vnějšího_parapetu: 0 m; Výška_vnitřního_parapetu: 0 m; Odstup_od_otvoru_dole: 0 m; Odstup_od_otvoru_nahoře: 0 m; Odstup_od_otvoru_vlevo: 0 m; Odstup_od_otvoru_vpravo: 0 m; Tloušťka_zárubně/rámu_dole: 0.02 m; Tloušťka_zárubně/rámu_vlevo: 0.02 m; Tloušťka_zárubně/rámu_vpravo: 0.02 m; Tloušťka_zárubně/rámu_nahoře: 0.02 m; Ochrana proti kouři: no; Nouzový východ: no; Bezpečnostní třída: bez; Zárubeň/Rám_Typ: Ocelový rám; Zárubeň/Rám_Materiál: Ocelová; Zárubeň/Rám_Povrch: Bílý lak; Křídlo_Materiál: Ocelové; Křídlo_Povrch_Int.: Bílý lak; Křídlo_Povrch_Ext.: Bílý lak; Kování_Klika_Ext.: není; Kování_Zámek: není; Kování_Klika_Int.: Okenní klika; Specifikace: Bemerkung mit max 254Zeichen; Height: 0.2 m; Length: 0.2 m; Kování_Závěsy: Celoobvodové kování s pětibodovým uzávěrem; Pset_BuildingElementProxyCommon - ThermalTransmittance: 0 W/K/m2
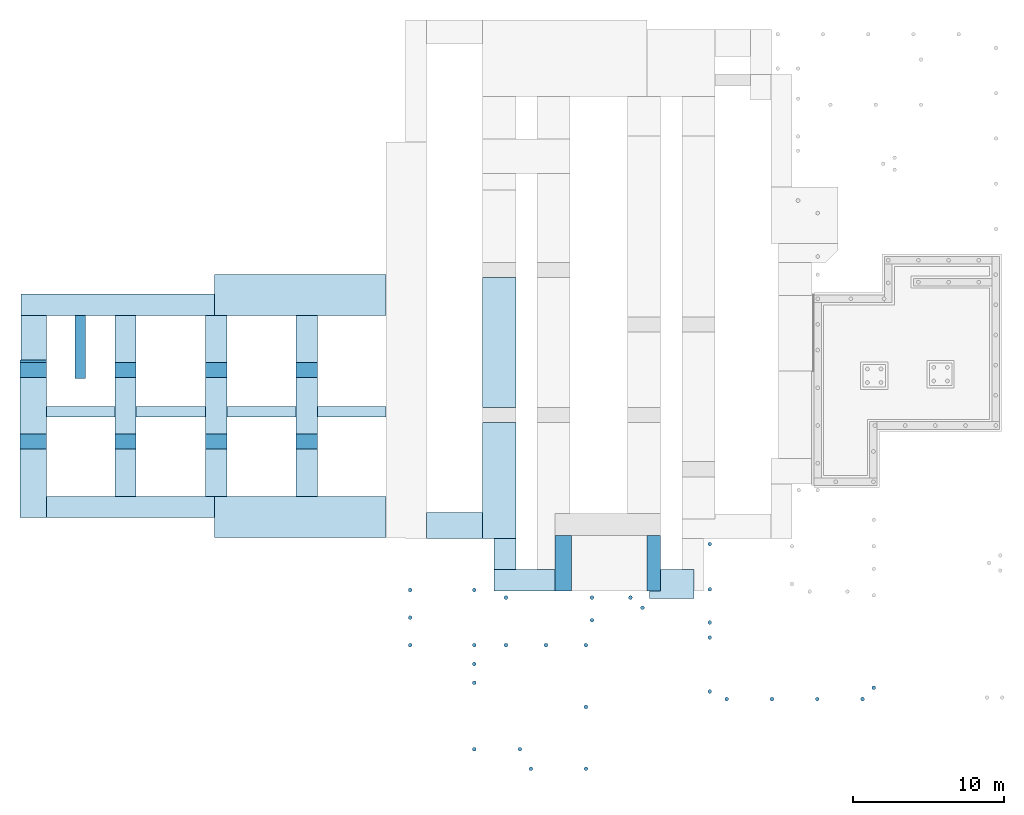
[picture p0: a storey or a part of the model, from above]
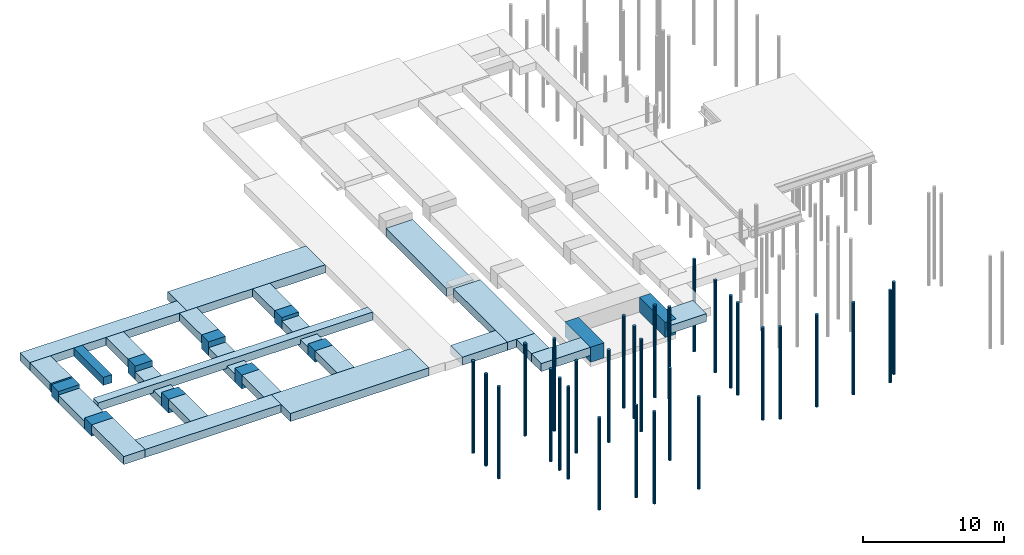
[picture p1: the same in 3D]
Properties of the parts of a building model (IFC4), part 2 of 45

# IfcBuildingElementProxy (404)
Name | In | Material | Práce | V6 (m) = V7 (m) = V8 (m) = V9 | Označení | Materiál | Allright_Stavebni_dil_ID | Jednotka | Název_objektu | NetSurfaceArea = NetVolume
 | Půdorys 1.PP |  |  | 0 |  |  | 1364Obj0798563426 | Kus | Okno - objekt+SmartPart | 1 | NEMSOK - Verze programu: 2.2; Plugin_Bezeichnung: MainObject; Plugin_Objektname: SmartPartCompressed; Verze: 3.0; Jednotková_cena: 0; Uvažované procento prosklení: 100; Plocha_skla: 0; Výška_vnějšího_parapetu: 0 m; Výška_vnitřního_parapetu: 0 m; Odstup_od_otvoru_dole: 0 m; Odstup_od_otvoru_nahoře: 0 m; Odstup_od_otvoru_vlevo: 0 m; Odstup_od_otvoru_vpravo: 0 m; Tloušťka_zárubně/rámu_dole: 0.02 m; Tloušťka_zárubně/rámu_vlevo: 0.02 m; Tloušťka_zárubně/rámu_vpravo: 0.02 m; Tloušťka_zárubně/rámu_nahoře: 0.02 m; Ochrana proti kouři: no; Nouzový východ: no; Bezpečnostní třída: bez; Zárubeň/Rám_Typ: Ocelový rám; Zárubeň/Rám_Materiál: Ocelová; Zárubeň/Rám_Povrch: Bílý lak; Křídlo_Materiál: Ocelové; Křídlo_Povrch_Int.: Bílý lak; Křídlo_Povrch_Ext.: Bílý lak; Kování_Klika_Ext.: není; Kování_Zámek: není; Kování_Klika_Int.: Okenní klika; Specifikace: Bemerkung mit max 254Zeichen; Height: 0.2 m; Length: 0.2 m; Kování_Závěsy: Celoobvodové kování s pětibodovým uzávěrem; Pset_BuildingElementProxyCommon - ThermalTransmittance: 0 W/K/m2
SDK INSTAL. PŘDSTĚNA NÍZKÁ | Půdorys 1.PP | SDK INSTAL. PŘDSTĚNA NÍZKÁ | Suché stavební práce |  | SDK INSTAL. PŘDSTĚNA NÍZKÁ | SDK INSTAL. PŘDSTĚNA NÍZKÁ | 1364Ind0000010795 | m3 | Instalační přizdívka | 1 | NEMSOK - Kód prvku: SN07.02.0001; Podlaží: 1.PP; Funkce (venkovní): Ne; 2D interakce: yes; Požární odolnost: bez požadavku; Vlhkostní namáhání oboustranné: Ne; Tloušťka opláštění: 2×12,5; Typ SDK desky: impregnovaná; Způsob opláštění: Jednostranné; Tloušťka izolace (2): 0; Objemová hmotnost izolace: 0; Typ profilu pro SDK: CW 50; Rozteč rastru: 625; Statická funkce: Ne; Pset_BuildingElementProxyCommon - Status: NEW; LoadBearing: no
Parapet vnější | Půdorys 1.NP | PLECH | Klempířské práce | 0 | Parapet vnější | PLECH | 1452Obj0798437609 | m | Parapet - objekt+SmartPart | 1 | NEMSOK - Absolutní_výška: 0.03 m; Tloušťka: 0.1 m; Výška: 0.005 m; Objem: 0.0012505; Plocha: 0.2156; Poloha (vnitřní/venkovní): 1
Parapet vnější | Půdorys 1.NP | PLECH | Klempířské práce | 0 | Parapet vnější | PLECH | 1452Obj0798437618 | m | Parapet - objekt+SmartPart | 1 | NEMSOK - Absolutní_výška: 0.03 m; Tloušťka: 0.1 m; Výška: 0.005 m; Objem: 0.0012505; Plocha: 0.2156; Poloha (vnitřní/venkovní): 1
Parapet vnější | Půdorys 1.NP | PLECH | Klempířské práce | 0 | Parapet vnější | PLECH | 1452Obj0798437627 | m | Parapet - objekt+SmartPart | 1 | NEMSOK - Absolutní_výška: 0.03 m; Tloušťka: 0.1 m; Výška: 0.005 m; Objem: 0.0012505; Plocha: 0.2156; Poloha (vnitřní/venkovní): 1
Parapet vnější | Půdorys 1.NP | PLECH | Klempířské práce | 0 | Parapet vnější | PLECH | 1452Obj0798437636 | m | Parapet - objekt+SmartPart | 1 | NEMSOK - Absolutní_výška: 0.03 m; Tloušťka: 0.1 m; Výška: 0.005 m; Objem: 0.0012505; Plocha: 0.2156; Poloha (vnitřní/venkovní): 1
Parapet vnější | Půdorys 1.NP | PLECH | Klempířské práce | 0 | Parapet vnější | PLECH | 1452Obj0798437645 | m | Parapet - objekt+SmartPart | 1 | NEMSOK - Absolutní_výška: 0.03 m; Tloušťka: 0.1 m; Výška: 0.005 m; Objem: 0.0012505; Plocha: 0.2156; Poloha (vnitřní/venkovní): 1
Parapet vnější | Půdorys 1.NP | PLECH | Klempířské práce | 0 | Parapet vnější | PLECH | 1452Obj0798437654 | m | Parapet - objekt+SmartPart | 1 | NEMSOK - Absolutní_výška: 0.03 m; Tloušťka: 0.1 m; Výška: 0.005 m; Objem: 0.0012505; Plocha: 0.2156; Poloha (vnitřní/venkovní): 1
Parapet vnější | Půdorys 1.NP | PLECH | Klempířské práce | 0 | Parapet vnější | PLECH | 1452Obj0798437663 | m | Parapet - objekt+SmartPart | 1 | NEMSOK - Absolutní_výška: 0.03 m; Tloušťka: 0.1 m; Výška: 0.005 m; Objem: 0.0012505; Plocha: 0.2156; Poloha (vnitřní/venkovní): 1
Parapet vnější | Půdorys 1.NP | PLECH | Klempířské práce | 0 | Parapet vnější | PLECH | 1452Obj0798437586 | m | Parapet - objekt+SmartPart | 1 | NEMSOK - Absolutní_výška: 0.03 m; Tloušťka: 0.1 m; Výška: 0.005 m; Objem: 0.0012505; Plocha: 0.2156; Poloha (vnitřní/venkovní): 1
Parapet vnější | Půdorys 1.NP | PLECH | Klempířské práce | 0 | Parapet vnější | PLECH | 1452Obj0798437794 | m | Parapet - objekt+SmartPart | 1 | NEMSOK - Absolutní_výška: 0.03 m; Tloušťka: 0.1 m; Výška: 0.005 m; Objem: 0.0012505; Plocha: 0.2156; Poloha (vnitřní/venkovní): 1
Parapet vnější | Půdorys 1.NP | PLECH | Klempířské práce | 0 | Parapet vnější | PLECH | 1452Obj0798437401 | m | Parapet - objekt+SmartPart | 1 | NEMSOK - Absolutní_výška: 0.03 m; Tloušťka: 0.1 m; Výška: 0.005 m; Objem: 0.0012505; Plocha: 0.2156; Poloha (vnitřní/venkovní): 1
Parapet vnější | Půdorys 1.NP | PLECH | Klempířské práce | 0 | Parapet vnější | PLECH | 1452Obj0798437410 | m | Parapet - objekt+SmartPart | 1 | NEMSOK - Absolutní_výška: 0.03 m; Tloušťka: 0.1 m; Výška: 0.005 m; Objem: 0.0012505; Plocha: 0.2156; Poloha (vnitřní/venkovní): 1
Parapet vnější | Půdorys 1.NP | PLECH | Klempířské práce | 0 | Parapet vnější | PLECH | 1452Obj0798437419 | m | Parapet - objekt+SmartPart | 1 | NEMSOK - Absolutní_výška: 0.03 m; Tloušťka: 0.1 m; Výška: 0.005 m; Objem: 0.0012505; Plocha: 0.2156; Poloha (vnitřní/venkovní): 1
Parapet vnější | Půdorys 1.NP | PLECH | Klempířské práce | 0 | Parapet vnější | PLECH | 1452Obj0798437428 | m | Parapet - objekt+SmartPart | 1 | NEMSOK - Absolutní_výška: 0.03 m; Tloušťka: 0.1 m; Výška: 0.005 m; Objem: 0.0012505; Plocha: 0.2156; Poloha (vnitřní/venkovní): 1
Parapet vnější | Půdorys 1.NP | PLECH | Klempířské práce | 0 | Parapet vnější | PLECH | 1452Obj0798437446 | m | Parapet - objekt+SmartPart | 1 | NEMSOK - Absolutní_výška: 0.03 m; Tloušťka: 0.1 m; Výška: 0.005 m; Objem: 0.0012505; Plocha: 0.2156; Poloha (vnitřní/venkovní): 1
Parapet vnější | Půdorys 1.NP | PLECH | Klempířské práce | 0 | Parapet vnější | PLECH | 1452Obj0798437455 | m | Parapet - objekt+SmartPart | 1 | NEMSOK - Absolutní_výška: 0.03 m; Tloušťka: 0.1 m; Výška: 0.005 m; Objem: 0.0012505; Plocha: 0.2156; Poloha (vnitřní/venkovní): 1
Parapet vnější | Půdorys 1.NP | PLECH | Klempířské práce | 0 | Parapet vnější | PLECH | 1452Obj0798437378 | m | Parapet - objekt+SmartPart | 1 | NEMSOK - Absolutní_výška: 0.03 m; Tloušťka: 0.1 m; Výška: 0.005 m; Objem: 0.0012505; Plocha: 0.2156; Poloha (vnitřní/venkovní): 1
Parapet vnější | Půdorys 1.NP | PLECH | Klempířské práce | 0 | Parapet vnější | PLECH | 1452Obj0798437437 | m | Parapet - objekt+SmartPart | 1 | NEMSOK - Absolutní_výška: 0.03 m; Tloušťka: 0.1 m; Výška: 0.005 m; Objem: 0.0012505; Plocha: 0.2156; Poloha (vnitřní/venkovní): 1
Ocelový profil | Půdorys 1.NP | U 140 |  | 0 | Ocelový profil | U 140 | 1452Sma0000001474 | Kus | SmartPart | 1 | NEMSOK - Verze programu: 1.0; Plugin_Bezeichnung: MainObject; Plugin_Objektname: SmartPartCompressed; Verze: 1.0; Dolní_hrana: 0 m; Horní_hrana: 0 m
Ocelový profil | Půdorys 1.NP | U 140 |  | 0 | Ocelový profil | U 140 | 1452Sma0000001473 | Kus | SmartPart | 1 | NEMSOK - Verze programu: 1.0; Plugin_Bezeichnung: MainObject; Plugin_Objektname: SmartPartCompressed; Verze: 1.0; Dolní_hrana: 0 m; Horní_hrana: 0 m
Parapet vnější | Půdorys 1.NP | PLECH | Klempířské práce | 0 | Parapet vnější | PLECH | 1452Obj0798439375 | m | Parapet - objekt+SmartPart | 1 | NEMSOK - Absolutní_výška: 0.03 m; Tloušťka: 0.1 m; Výška: 0.005 m; Objem: 0.0012505; Plocha: 0.2156; Poloha (vnitřní/venkovní): 1
Parapet vnější | Půdorys 1.NP | PLECH | Klempířské práce | 0 | Parapet vnější | PLECH | 1452Obj0798439353 | m | Parapet - objekt+SmartPart | 1 | NEMSOK - Absolutní_výška: 0.03 m; Tloušťka: 0.1 m; Výška: 0.005 m; Objem: 0.0012505; Plocha: 0.2156; Poloha (vnitřní/venkovní): 1
Parapet vnější | Půdorys 1.NP | PLECH | Klempířské práce | 0 | Parapet vnější | PLECH | 1452Obj0798439273 | m | Parapet - objekt+SmartPart | 1 | NEMSOK - Absolutní_výška: 0.03 m; Tloušťka: 0.1 m; Výška: 0.005 m; Objem: 0.0012505; Plocha: 0.2156; Poloha (vnitřní/venkovní): 1
Parapet vnější | Půdorys 1.NP | PLECH | Klempířské práce | 0 | Parapet vnější | PLECH | 1452Obj0798439160 | m | Parapet - objekt+SmartPart | 1 | NEMSOK - Absolutní_výška: 0.03 m; Tloušťka: 0.1 m; Výška: 0.005 m; Objem: 0.001003; Plocha: 0.1736; Poloha (vnitřní/venkovní): 1
Parapet vnější | Půdorys 1.NP | PLECH | Klempířské práce | 0 | Parapet vnější | PLECH | 1452Obj0798439169 | m | Parapet - objekt+SmartPart | 1 | NEMSOK - Absolutní_výška: 0.03 m; Tloušťka: 0.1 m; Výška: 0.005 m; Objem: 0.001003; Plocha: 0.1736; Poloha (vnitřní/venkovní): 1
Parapet vnější | Půdorys 1.NP | PLECH | Klempířské práce | 0 | Parapet vnější | PLECH | 1452Obj0798439137 | m | Parapet - objekt+SmartPart | 1 | NEMSOK - Absolutní_výška: 0.03 m; Tloušťka: 0.1 m; Výška: 0.005 m; Objem: 0.001003; Plocha: 0.1736; Poloha (vnitřní/venkovní): 1
Parapet vnější | Půdorys 1.NP | PLECH | Klempířské práce | 0 | Parapet vnější | PLECH | 1452Obj0798439451 | m | Parapet - objekt+SmartPart | 1 | NEMSOK - Absolutní_výška: 0.03 m; Tloušťka: 0.1 m; Výška: 0.005 m; Objem: 0.00087925; Plocha: 0.1526; Poloha (vnitřní/venkovní): 1
YTONG INSTALAČNÍ PŘEDSTĚNA | Půdorys 1.NP | YTONG INSTALAČNÍ PŘEDSTĚNA | Zednické práce |  | YTONG INSTALAČNÍ PŘEDSTĚNA | YTONG INSTALAČNÍ PŘEDSTĚNA | 1452Ind1096101364 | m2 | Instalační přizdívka | 1 | Pset_BuildingElementProxyCommon - Status: EXISTING; LoadBearing: no
YTONG INSTALAČNÍ PŘEDSTĚNA | Půdorys 1.NP | YTONG INSTALAČNÍ PŘEDSTĚNA | Zednické práce |  | YTONG INSTALAČNÍ PŘEDSTĚNA | YTONG INSTALAČNÍ PŘEDSTĚNA | 1452Ind1096101355 | m2 | Instalační přizdívka | 1 | Pset_BuildingElementProxyCommon - Status: EXISTING; LoadBearing: no
 | Půdorys 1.NP | VĚTRACÍ KOMÍN |  |  |  | VĚTRACÍ KOMÍN | 1452ExE0798445538 | m3 | Rozšířený element | 1
 | Půdorys 1.NP | DVEŘNÍ POHON |  |  |  | DVEŘNÍ POHON | 1452ExE1096112786 | m3 | Rozšířený element | 1
YTONG INSTALAČNÍ PŘEDSTĚNA | Půdorys 1.NP | YTONG INSTALAČNÍ PŘEDSTĚNA | Zednické práce |  | YTONG INSTALAČNÍ PŘEDSTĚNA | YTONG INSTALAČNÍ PŘEDSTĚNA | 1452Ind1096115446 | m2 | Instalační přizdívka | 1 | Pset_BuildingElementProxyCommon - Status: EXISTING; LoadBearing: no
YTONG INSTALAČNÍ PŘEDSTĚNA | Půdorys 1.NP | YTONG INSTALAČNÍ PŘEDSTĚNA | Zednické práce |  | YTONG INSTALAČNÍ PŘEDSTĚNA | YTONG INSTALAČNÍ PŘEDSTĚNA | 1452Ind1096115439 | m2 | Instalační přizdívka | 1 | Pset_BuildingElementProxyCommon - Status: EXISTING; LoadBearing: no
YTONG INSTALAČNÍ PŘEDSTĚNA | Půdorys 1.NP | YTONG INSTALAČNÍ PŘEDSTĚNA | Zednické práce |  | YTONG INSTALAČNÍ PŘEDSTĚNA | YTONG INSTALAČNÍ PŘEDSTĚNA | 1452Ind1096118670 | m2 | Instalační přizdívka | 1 | Pset_BuildingElementProxyCommon - Status: EXISTING; LoadBearing: no
YTONG INSTALAČNÍ PŘEDSTĚNA | Půdorys 1.NP | YTONG INSTALAČNÍ PŘEDSTĚNA | Zednické práce |  | YTONG INSTALAČNÍ PŘEDSTĚNA | YTONG INSTALAČNÍ PŘEDSTĚNA | 1452Ind1096118677 | m2 | Instalační přizdívka | 1 | Pset_BuildingElementProxyCommon - Status: EXISTING; LoadBearing: no
Parapet vnější | Půdorys 1.NP | PLECH | Klempířské práce | 0 | Parapet vnější | PLECH | 1452Obj1096106995 | m | Parapet - objekt+SmartPart | 1 | NEMSOK - Absolutní_výška: 0.03 m; Tloušťka: 0.2 m; Výška: 0.005 m; Objem: 0.0020005; Plocha: 0.3696; Poloha (vnitřní/venkovní): 1
Parapet vnější | Půdorys 1.NP | PLECH | Klempířské práce | 0 | Parapet vnější | PLECH | 1452Obj1096107042 | m | Parapet - objekt+SmartPart | 1 | NEMSOK - Absolutní_výška: 0.03 m; Tloušťka: 0.2 m; Výška: 0.005 m; Objem: 0.0020005; Plocha: 0.3696; Poloha (vnitřní/venkovní): 1
Parapet vnější | Půdorys 1.NP | PLECH | Klempířské práce | 0 | Parapet vnější | PLECH | 1452Obj1096107089 | m | Parapet - objekt+SmartPart | 1 | NEMSOK - Absolutní_výška: 0.03 m; Tloušťka: 0.2 m; Výška: 0.005 m; Objem: 0.0020005; Plocha: 0.3696; Poloha (vnitřní/venkovní): 1
YTONG INSTALAČNÍ PŘEDSTĚNA | Půdorys 1.NP | YTONG INSTALAČNÍ PŘEDSTĚNA | Zednické práce |  | YTONG INSTALAČNÍ PŘEDSTĚNA | YTONG INSTALAČNÍ PŘEDSTĚNA | 1452Ind1096115691 | m2 | Instalační přizdívka | 1 | Pset_BuildingElementProxyCommon - Status: EXISTING; LoadBearing: no
YTONG INSTALAČNÍ PŘEDSTĚNA | Půdorys 1.NP | YTONG INSTALAČNÍ PŘEDSTĚNA | Zednické práce |  | YTONG INSTALAČNÍ PŘEDSTĚNA | YTONG INSTALAČNÍ PŘEDSTĚNA | 1452Ind1096114652 | m2 | Instalační přizdívka | 1 | Pset_BuildingElementProxyCommon - Status: EXISTING; LoadBearing: no
YTONG INSTALAČNÍ PŘEDSTĚNA | Půdorys 1.NP | YTONG INSTALAČNÍ PŘEDSTĚNA | Zednické práce |  | YTONG INSTALAČNÍ PŘEDSTĚNA | YTONG INSTALAČNÍ PŘEDSTĚNA | 1452Ind1096115427 | m2 | Instalační přizdívka | 1 | Pset_BuildingElementProxyCommon - Status: EXISTING; LoadBearing: no
YTONG INSTALAČNÍ PŘEDSTĚNA | Půdorys 1.NP | YTONG INSTALAČNÍ PŘEDSTĚNA | Zednické práce |  | YTONG INSTALAČNÍ PŘEDSTĚNA | YTONG INSTALAČNÍ PŘEDSTĚNA | 1452Ind1096115417 | m2 | Instalační přizdívka | 1 | Pset_BuildingElementProxyCommon - Status: EXISTING; LoadBearing: no
STŘÍŠKA NAD VCHODEM | Půdorys 1.NP |  |  | 0 | STŘÍŠKA NAD VCHODEM |  | 1464Obj1096288659 | Kus | II.SS | 1
 | Půdorys 1.NP | DVEŘNÍ POHON |  |  |  | DVEŘNÍ POHON | 1464ExE1096106926 | m3 | Rozšířený element | 1 | NEMSOK - Kód prvku: DD03.03.2001
 | Půdorys 1.NP | DVEŘNÍ POHON |  |  |  | DVEŘNÍ POHON | 1464ExE1096158513 | m3 | Kvádr | 1 | NEMSOK - Kód prvku: DD03.03.1201
 | Půdorys 1.NP | DVEŘNÍ POHON |  |  |  | DVEŘNÍ POHON | 1464ExE1096158512 | m3 | Kvádr | 1 | NEMSOK - Kód prvku: DD03.03.1101
 | Půdorys 1.NP | DVEŘNÍ POHON |  |  |  | DVEŘNÍ POHON | 1464ExE1096158425 | m3 | Kvádr | 1 | NEMSOK - Kód prvku: DD03.03.1202
 | Půdorys 1.NP | DVEŘNÍ POHON |  |  |  | DVEŘNÍ POHON | 1464ExE1096158426 | m3 | Kvádr | 1 | NEMSOK - Kód prvku: DD03.03.1203
 | Půdorys 1.NP | DVEŘNÍ POHON |  |  |  | DVEŘNÍ POHON | 1464ExE1096158438 | m3 | Kvádr | 1 | NEMSOK - Kód prvku: DD03.03.1204
 | Půdorys 1.NP | DVEŘNÍ POHON |  |  |  | DVEŘNÍ POHON | 1464ExE1096157264 | m3 | Kvádr | 1 | NEMSOK - Kód prvku: DD03.03.1206
 | Půdorys 1.NP | DVEŘNÍ POHON |  |  |  | DVEŘNÍ POHON | 1464ExE1096209026 | m3 | Kvádr | 1 | NEMSOK - Kód prvku: DD03.03.1221
 | Půdorys 1.NP | DVEŘNÍ POHON |  |  |  | DVEŘNÍ POHON | 1464ExE1096159322 | m3 | Kvádr | 1 | NEMSOK - Kód prvku: DD03.03.1102
 | Půdorys 1.NP | DVEŘNÍ POHON |  |  |  | DVEŘNÍ POHON | 1464ExE1096213837 | m3 | Kvádr | 1 | NEMSOK - Kód prvku: DD03.03.1207
 | Půdorys 1.NP | DVEŘNÍ POHON |  |  |  | DVEŘNÍ POHON | 1464ExE1096215055 | m3 | Kvádr | 1 | NEMSOK - Kód prvku: DD03.03.1208
 | Půdorys 1.NP | DVEŘNÍ POHON |  |  |  | DVEŘNÍ POHON | 1464ExE1096214772 | m3 | Kvádr | 1 | NEMSOK - Kód prvku: DD03.03.1209
 | Půdorys 1.NP | DVEŘNÍ POHON |  |  |  | DVEŘNÍ POHON | 1464ExE1096214664 | m3 | Kvádr | 1 | NEMSOK - Kód prvku: DD03.03.1210
 | Půdorys 1.NP | DVEŘNÍ POHON |  |  |  | DVEŘNÍ POHON | 1464ExE1096214806 | m3 | Kvádr | 1 | NEMSOK - Kód prvku: DD03.03.1211
 | Půdorys 1.NP | DVEŘNÍ POHON |  |  |  | DVEŘNÍ POHON | 1464ExE1096158437 | m3 | Kvádr | 1 | NEMSOK - Kód prvku: DD03.03.1212
 | Půdorys 1.NP | DVEŘNÍ POHON |  |  |  | DVEŘNÍ POHON | 1464ExE1096158436 | m3 | Kvádr | 1 | NEMSOK - Kód prvku: DD03.03.1214
 | Půdorys 1.NP | DVEŘNÍ POHON |  |  |  | DVEŘNÍ POHON | 1464ExE1096171621 | m3 | Kvádr | 1 | NEMSOK - Kód prvku: DD03.03.1216
 | Půdorys 1.NP | DVEŘNÍ POHON |  |  |  | DVEŘNÍ POHON | 1464ExE1096171623 | m3 | Kvádr | 1 | NEMSOK - Kód prvku: DD03.03.1218
 | Půdorys 1.NP | DVEŘNÍ POHON |  |  |  | DVEŘNÍ POHON | 1464ExE1096171624 | m3 | Kvádr | 1 | NEMSOK - Kód prvku: DD03.03.1219
 | Půdorys 1.NP | KOLEJNICE POSUVNÝCH DVEŘÍ |  |  |  | KOLEJNICE POSUVNÝCH DVEŘÍ | 1464ExE1096158435 | m3 | Kvádr | 1 | NEMSOK - Kód prvku: DD03.03.1301
 | Půdorys 1.NP | KOLEJNICE POSUVNÝCH DVEŘÍ |  |  |  | KOLEJNICE POSUVNÝCH DVEŘÍ | 1464ExE1096169008 | m3 | Kvádr | 1 | NEMSOK - Kód prvku: DD03.03.1302
 | Půdorys 1.NP | KOLEJNICE POSUVNÝCH DVEŘÍ |  |  |  | KOLEJNICE POSUVNÝCH DVEŘÍ | 1464ExE1096169009 | m3 | Kvádr | 1 | NEMSOK - Kód prvku: DD03.03.1303
 | Půdorys 1.NP | KOLEJNICE POSUVNÝCH DVEŘÍ |  |  |  | KOLEJNICE POSUVNÝCH DVEŘÍ | 1464ExE1096169010 | m3 | Kvádr | 1 | NEMSOK - Kód prvku: DD03.03.1304
 | Půdorys 1.NP | DVEŘNÍ POHON |  |  |  | DVEŘNÍ POHON | 1464ExE1096175733 | m3 | Kvádr | 1 | NEMSOK - Kód prvku: DD03.03.1213
Parapet vnější | Půdorys 1.NP | HLINÍKOVÝ PLECH ELOXOVANÝ | Klempířské práce | 0 | Parapet vnější | HLINÍKOVÝ PLECH ELOXOVANÝ | 1464Obj1096219336 | m | Parapet - objekt+SmartPart | 1 | NEMSOK - Absolutní_výška: 0.03 m; Tloušťka: 0.205 m; Výška: 0.005 m; Poloha (vnitřní/venkovní): 1; Kód prvku: ON03.03.2001; Podlaží: 1.NP; Rozvinutá šířka: 0.33 m; Pset_BuildingElementProxyCommon - Status: NEW
Parapet vnější | Půdorys 1.NP | HLINÍKOVÝ PLECH ELOXOVANÝ | Klempířské práce | 0 | Parapet vnější | HLINÍKOVÝ PLECH ELOXOVANÝ | 1464Obj1096168463 | m | Parapet - objekt+SmartPart | 1 | NEMSOK - Absolutní_výška: 0.03 m; Tloušťka: 0.208 m; Výška: 0.005 m; Poloha (vnitřní/venkovní): 1; Kód prvku: ON03.03.1001; Podlaží: 1.NP; Rozvinutá šířka: 0.33 m; Pset_BuildingElementProxyCommon - Status: NEW
Žaluzie | Půdorys 1.NP |  |  | 0 | Žaluzie |  | 1464Obj1096231576 | Kus | Zastínění | 1 | NEMSOK - Kód prvku: ON03.03.1001; Podlaží: 1.NP; Verze programu: 2.1; Plugin_Bezeichnung: MainObject; Plugin_Objektname: SmartPartCompressed; Verze: 2.1; Připojení NN: Ano; Pset_BuildingElementProxyCommon - Status: NEW
Parapet vnější | Půdorys 1.NP | HLINÍKOVÝ PLECH ELOXOVANÝ | Klempířské práce | 0 | Parapet vnější | HLINÍKOVÝ PLECH ELOXOVANÝ | 1464Obj1096168519 | m | Parapet - objekt+SmartPart | 1 | NEMSOK - Absolutní_výška: 0.03 m; Tloušťka: 0.208 m; Výška: 0.005 m; Poloha (vnitřní/venkovní): 1; Kód prvku: ON03.03.1001; Podlaží: 1.NP; Rozvinutá šířka: 0.33 m; Pset_BuildingElementProxyCommon - Status: NEW
Žaluzie | Půdorys 1.NP |  |  | 0 | Žaluzie |  | 1464Obj1096231579 | Kus | Zastínění | 1 | NEMSOK - Kód prvku: ON03.03.1001; Podlaží: 1.NP; Verze programu: 2.1; Plugin_Bezeichnung: MainObject; Plugin_Objektname: SmartPartCompressed; Verze: 2.1; Připojení NN: Ano; Pset_BuildingElementProxyCommon - Status: NEW
Parapet vnější | Půdorys 1.NP | HLINÍKOVÝ PLECH ELOXOVANÝ | Klempířské práce | 0 | Parapet vnější | HLINÍKOVÝ PLECH ELOXOVANÝ | 1464Obj1096168545 | m | Parapet - objekt+SmartPart | 1 | NEMSOK - Absolutní_výška: 0.03 m; Tloušťka: 0.208 m; Výška: 0.005 m; Poloha (vnitřní/venkovní): 1; Kód prvku: ON03.03.1001; Podlaží: 1.NP; Rozvinutá šířka: 0.33 m; Pset_BuildingElementProxyCommon - Status: NEW
Žaluzie | Půdorys 1.NP |  |  | 0 | Žaluzie |  | 1464Obj1096231582 | Kus | Zastínění | 1 | NEMSOK - Kód prvku: ON03.03.1001; Podlaží: 1.NP; Verze programu: 2.1; Plugin_Bezeichnung: MainObject; Plugin_Objektname: SmartPartCompressed; Verze: 2.1; Připojení NN: Ano; Pset_BuildingElementProxyCommon - Status: NEW
Parapet vnější | Půdorys 1.NP | HLINÍKOVÝ PLECH ELOXOVANÝ | Klempířské práce | 0 | Parapet vnější | HLINÍKOVÝ PLECH ELOXOVANÝ | 1464Obj1096168606 | m | Parapet - objekt+SmartPart | 1 | NEMSOK - Absolutní_výška: 0.03 m; Tloušťka: 0.208 m; Výška: 0.005 m; Poloha (vnitřní/venkovní): 1; Kód prvku: ON03.03.1001; Podlaží: 1.NP; Rozvinutá šířka: 0.33 m; Pset_BuildingElementProxyCommon - Status: NEW
Žaluzie | Půdorys 1.NP |  |  | 0 | Žaluzie |  | 1464Obj1096231618 | Kus | Zastínění | 1 | NEMSOK - Kód prvku: ON03.03.1001; Podlaží: 1.NP; Verze programu: 2.1; Plugin_Bezeichnung: MainObject; Plugin_Objektname: SmartPartCompressed; Verze: 2.1; Připojení NN: Ano; Pset_BuildingElementProxyCommon - Status: NEW
Parapet vnější | Půdorys 1.NP | HLINÍKOVÝ PLECH ELOXOVANÝ | Klempířské práce | 0 | Parapet vnější | HLINÍKOVÝ PLECH ELOXOVANÝ | 1464Obj1096168641 | m | Parapet - objekt+SmartPart | 1 | NEMSOK - Absolutní_výška: 0.03 m; Tloušťka: 0.208 m; Výška: 0.005 m; Poloha (vnitřní/venkovní): 1; Kód prvku: ON03.03.1001; Podlaží: 1.NP; Rozvinutá šířka: 0.33 m; Pset_BuildingElementProxyCommon - Status: NEW
Žaluzie | Půdorys 1.NP |  |  | 0 | Žaluzie |  | 1464Obj1096231621 | Kus | Zastínění | 1 | NEMSOK - Kód prvku: ON03.03.1001; Podlaží: 1.NP; Verze programu: 2.1; Plugin_Bezeichnung: MainObject; Plugin_Objektname: SmartPartCompressed; Verze: 2.1; Připojení NN: Ano; Pset_BuildingElementProxyCommon - Status: NEW
Parapet vnější | Půdorys 1.NP | HLINÍKOVÝ PLECH ELOXOVANÝ | Klempířské práce | 0 | Parapet vnější | HLINÍKOVÝ PLECH ELOXOVANÝ | 1464Obj1096168672 | m | Parapet - objekt+SmartPart | 1 | NEMSOK - Absolutní_výška: 0.03 m; Tloušťka: 0.208 m; Výška: 0.005 m; Poloha (vnitřní/venkovní): 1; Kód prvku: ON03.03.1001; Podlaží: 1.NP; Rozvinutá šířka: 0.33 m; Pset_BuildingElementProxyCommon - Status: NEW
Žaluzie | Půdorys 1.NP |  |  | 0 | Žaluzie |  | 1464Obj1096231624 | Kus | Zastínění | 1 | NEMSOK - Kód prvku: ON03.03.1001; Podlaží: 1.NP; Verze programu: 2.1; Plugin_Bezeichnung: MainObject; Plugin_Objektname: SmartPartCompressed; Verze: 2.1; Připojení NN: Ano; Pset_BuildingElementProxyCommon - Status: NEW
Parapet vnější | Půdorys 1.NP | HLINÍKOVÝ PLECH ELOXOVANÝ | Klempířské práce | 0 | Parapet vnější | HLINÍKOVÝ PLECH ELOXOVANÝ | 1464Obj1096174653 | m | Parapet - objekt+SmartPart | 1 | NEMSOK - Absolutní_výška: 0.03 m; Tloušťka: 0.208 m; Výška: 0.005 m; Poloha (vnitřní/venkovní): 1; Kód prvku: ON03.03.1001; Podlaží: 1.NP; Rozvinutá šířka: 0.33 m; Pset_BuildingElementProxyCommon - Status: NEW
Žaluzie | Půdorys 1.NP |  |  | 0 | Žaluzie |  | 1464Obj1096231585 | Kus | Zastínění | 1 | NEMSOK - Kód prvku: ON03.03.1001; Podlaží: 1.NP; Verze programu: 2.1; Plugin_Bezeichnung: MainObject; Plugin_Objektname: SmartPartCompressed; Verze: 2.1; Připojení NN: Ano; Pset_BuildingElementProxyCommon - Status: NEW
Parapet vnější | Půdorys 1.NP | HLINÍKOVÝ PLECH ELOXOVANÝ | Klempířské práce | 0 | Parapet vnější | HLINÍKOVÝ PLECH ELOXOVANÝ | 1464Obj1096167916 | m | Parapet - objekt+SmartPart | 1 | NEMSOK - Absolutní_výška: 0.03 m; Tloušťka: 0.208 m; Výška: 0.005 m; Poloha (vnitřní/venkovní): 1; Kód prvku: ON03.03.1001; Podlaží: 1.NP; Rozvinutá šířka: 0.33 m; Pset_BuildingElementProxyCommon - Status: NEW
Žaluzie | Půdorys 1.NP |  |  | 0 | Žaluzie |  | 1464Obj1096231573 | Kus | Zastínění | 1 | NEMSOK - Kód prvku: ON03.03.1001; Podlaží: 1.NP; Verze programu: 2.1; Plugin_Bezeichnung: MainObject; Plugin_Objektname: SmartPartCompressed; Verze: 2.1; Připojení NN: Ano; Pset_BuildingElementProxyCommon - Status: NEW
Parapet vnější | Půdorys 1.NP | HLINÍKOVÝ PLECH ELOXOVANÝ | Klempířské práce | 0 | Parapet vnější | HLINÍKOVÝ PLECH ELOXOVANÝ | 1464Obj1096168849 | m | Parapet - objekt+SmartPart | 1 | NEMSOK - Absolutní_výška: 0.03 m; Tloušťka: 0.208 m; Výška: 0.005 m; Objem: 0.0020605; Plocha: 0.38192; Poloha (vnitřní/venkovní): 1; Kód prvku: ON03.03.1001; Podlaží: 1.NP; Rozvinutá šířka: 0.33 m; Pset_BuildingElementProxyCommon - Status: NEW
Žaluzie | Půdorys 1.NP |  |  | 0 | Žaluzie |  | 1464Obj1096231627 | Kus | Zastínění | 1 | NEMSOK - Kód prvku: ON03.03.1001; Podlaží: 1.NP; Verze programu: 2.1; Plugin_Bezeichnung: MainObject; Plugin_Objektname: SmartPartCompressed; Verze: 2.1; Připojení NN: Ano; Pset_BuildingElementProxyCommon - Status: NEW
Parapet vnější | Půdorys 1.NP | HLINÍKOVÝ PLECH ELOXOVANÝ | Klempířské práce | 0 | Parapet vnější | HLINÍKOVÝ PLECH ELOXOVANÝ | 1464Obj1096168868 | m | Parapet - objekt+SmartPart | 1 | NEMSOK - Absolutní_výška: 0.03 m; Tloušťka: 0.208 m; Výška: 0.005 m; Objem: 0.0020605; Plocha: 0.38192; Poloha (vnitřní/venkovní): 1; Kód prvku: ON03.03.1001; Podlaží: 1.NP; Rozvinutá šířka: 0.33 m; Pset_BuildingElementProxyCommon - Status: NEW
Žaluzie | Půdorys 1.NP |  |  | 0 | Žaluzie |  | 1464Obj1096231630 | Kus | Zastínění | 1 | NEMSOK - Kód prvku: ON03.03.1001; Podlaží: 1.NP; Verze programu: 2.1; Plugin_Bezeichnung: MainObject; Plugin_Objektname: SmartPartCompressed; Verze: 2.1; Připojení NN: Ano; Pset_BuildingElementProxyCommon - Status: NEW
Parapet vnější | Půdorys 1.NP | HLINÍKOVÝ PLECH ELOXOVANÝ | Klempířské práce | 0 | Parapet vnější | HLINÍKOVÝ PLECH ELOXOVANÝ | 1464Obj1096168893 | m | Parapet - objekt+SmartPart | 1 | NEMSOK - Absolutní_výška: 0.03 m; Tloušťka: 0.208 m; Výška: 0.005 m; Objem: 0.0020605; Plocha: 0.38192; Poloha (vnitřní/venkovní): 1; Kód prvku: ON03.03.1001; Podlaží: 1.NP; Rozvinutá šířka: 0.33 m; Pset_BuildingElementProxyCommon - Status: NEW
Žaluzie | Půdorys 1.NP |  |  | 0 | Žaluzie |  | 1464Obj1096231633 | Kus | Zastínění | 1 | NEMSOK - Kód prvku: ON03.03.1001; Podlaží: 1.NP; Verze programu: 2.1; Plugin_Bezeichnung: MainObject; Plugin_Objektname: SmartPartCompressed; Verze: 2.1; Připojení NN: Ano; Pset_BuildingElementProxyCommon - Status: NEW
Parapet vnější | Půdorys 1.NP | HLINÍKOVÝ PLECH ELOXOVANÝ | Klempířské práce | 0 | Parapet vnější | HLINÍKOVÝ PLECH ELOXOVANÝ | 1464Obj1096168924 | m | Parapet - objekt+SmartPart | 1 | NEMSOK - Absolutní_výška: 0.03 m; Tloušťka: 0.208 m; Výška: 0.005 m; Objem: 0.0020605; Plocha: 0.38192; Poloha (vnitřní/venkovní): 1; Kód prvku: ON03.03.1001; Podlaží: 1.NP; Rozvinutá šířka: 0.33 m; Pset_BuildingElementProxyCommon - Status: NEW
Žaluzie | Půdorys 1.NP |  |  | 0 | Žaluzie |  | 1464Obj1096231636 | Kus | Zastínění | 1 | NEMSOK - Kód prvku: ON03.03.1001; Podlaží: 1.NP; Verze programu: 2.1; Plugin_Bezeichnung: MainObject; Plugin_Objektname: SmartPartCompressed; Verze: 2.1; Připojení NN: Ano; Pset_BuildingElementProxyCommon - Status: NEW
Parapet vnější | Půdorys 1.NP | HLINÍKOVÝ PLECH ELOXOVANÝ | Klempířské práce | 0 | Parapet vnější | HLINÍKOVÝ PLECH ELOXOVANÝ | 1464Obj1096168140 | m | Parapet - objekt+SmartPart | 1 | NEMSOK - Absolutní_výška: 0.03 m; Tloušťka: 0.208 m; Výška: 0.005 m; Poloha (vnitřní/venkovní): 1; Kód prvku: ON03.03.1001; Podlaží: 1.NP; Rozvinutá šířka: 0.33 m; Pset_BuildingElementProxyCommon - Status: NEW
Žaluzie | Půdorys 1.NP |  |  | 0 | Žaluzie |  | 1464Obj1096231399 | Kus | Zastínění | 1 | NEMSOK - Kód prvku: ON03.03.1001; Podlaží: 1.NP; Verze programu: 2.1; Plugin_Bezeichnung: MainObject; Plugin_Objektname: SmartPartCompressed; Verze: 2.1; Připojení NN: Ano; Pset_BuildingElementProxyCommon - Status: NEW
Parapet vnější | Půdorys 1.NP | HLINÍKOVÝ PLECH ELOXOVANÝ | Klempířské práce | 0 | Parapet vnější | HLINÍKOVÝ PLECH ELOXOVANÝ | 1464Obj1096168171 | m | Parapet - objekt+SmartPart | 1 | NEMSOK - Absolutní_výška: 0.03 m; Tloušťka: 0.208 m; Výška: 0.005 m; Poloha (vnitřní/venkovní): 1; Kód prvku: ON03.03.1001; Podlaží: 1.NP; Rozvinutá šířka: 0.33 m; Pset_BuildingElementProxyCommon - Status: NEW
Žaluzie | Půdorys 1.NP |  |  | 0 | Žaluzie |  | 1464Obj1096231570 | Kus | Zastínění | 1 | NEMSOK - Kód prvku: ON03.03.1001; Podlaží: 1.NP; Verze programu: 2.1; Plugin_Bezeichnung: MainObject; Plugin_Objektname: SmartPartCompressed; Verze: 2.1; Připojení NN: Ano; Pset_BuildingElementProxyCommon - Status: NEW
 | Půdorys 1.NP | DVEŘNÍ POHON |  |  |  | DVEŘNÍ POHON | 1464ExE1096157301 | m3 | Kvádr | 1 | NEMSOK - Kód prvku: DD03.03.1205
 | Půdorys 1.NP | DVEŘNÍ POHON |  |  |  | DVEŘNÍ POHON | 1464ExE1096158427 | m3 | Kvádr | 1 | NEMSOK - Kód prvku: DD03.03.1215
 | Půdorys 1.NP | DVEŘNÍ POHON |  |  |  | DVEŘNÍ POHON | 1464ExE1096171622 | m3 | Kvádr | 1 | NEMSOK - Kód prvku: DD03.03.1217
I.Z6 | Půdorys 1.NP |  |  | 0 | I.Z6 |  | 1464Obj1096313510 | Kus | Okno - objekt+SmartPart | 1 | NEMSOK - Verze programu: 2.2; Plugin_Bezeichnung: MainObject; Plugin_Objektname: SmartPartCompressed; Verze: 3.0; Jednotková_cena: 0; Uvažované procento prosklení: 100; Plocha_skla: 0; Výška_vnějšího_parapetu: 0 m; Výška_vnitřního_parapetu: 0 m; Odstup_od_otvoru_dole: 0 m; Odstup_od_otvoru_nahoře: 0 m; Odstup_od_otvoru_vlevo: 0 m; Odstup_od_otvoru_vpravo: 0 m; Tloušťka_zárubně/rámu_dole: 0.02 m; Tloušťka_zárubně/rámu_vlevo: 0.02 m; Tloušťka_zárubně/rámu_vpravo: 0.02 m; Tloušťka_zárubně/rámu_nahoře: 0.02 m; Ochrana proti kouři: no; Nouzový východ: no; Bezpečnostní třída: SA; Zárubeň/Rám_Typ: Dřevěný rám 92 mm; Zárubeň/Rám_Materiál: Dřevěný lepený eurohranol; Zárubeň/Rám_Povrch: Bílý lak; Křídlo_Materiál: Dřevěný lepený eurohranol; Křídlo_Povrch_Int.: Bílý lak; Křídlo_Povrch_Ext.: Bílý lak; Kování_Klika_Ext.: není; Kování_Zámek: není; Kování_Klika_Int.: Okenní klika; Specifikace: Bemerkung mit max 254Zeichen; Kování_Závěsy: Celoobvodové kování s pětibodovým uzávěrem; Pset_BuildingElementProxyCommon - ThermalTransmittance: 0.8 W/K/m2
I.Z6 | Půdorys 1.NP |  |  | 0 | I.Z6 |  | 1464Obj1096313525 | Kus | Okno - objekt+SmartPart | 1 | NEMSOK - Verze programu: 2.2; Plugin_Bezeichnung: MainObject; Plugin_Objektname: SmartPartCompressed; Verze: 3.0; Jednotková_cena: 0; Uvažované procento prosklení: 100; Plocha_skla: 0; Výška_vnějšího_parapetu: 0 m; Výška_vnitřního_parapetu: 0 m; Odstup_od_otvoru_dole: 0 m; Odstup_od_otvoru_nahoře: 0 m; Odstup_od_otvoru_vlevo: 0 m; Odstup_od_otvoru_vpravo: 0 m; Tloušťka_zárubně/rámu_dole: 0.02 m; Tloušťka_zárubně/rámu_vlevo: 0.02 m; Tloušťka_zárubně/rámu_vpravo: 0.02 m; Tloušťka_zárubně/rámu_nahoře: 0.02 m; Ochrana proti kouři: no; Nouzový východ: no; Bezpečnostní třída: SA; Zárubeň/Rám_Typ: Dřevěný rám 92 mm; Zárubeň/Rám_Materiál: Dřevěný lepený eurohranol; Zárubeň/Rám_Povrch: Bílý lak; Křídlo_Materiál: Dřevěný lepený eurohranol; Křídlo_Povrch_Int.: Bílý lak; Křídlo_Povrch_Ext.: Bílý lak; Kování_Klika_Ext.: není; Kování_Zámek: není; Kování_Klika_Int.: Okenní klika; Specifikace: Bemerkung mit max 254Zeichen; Kování_Závěsy: Celoobvodové kování s pětibodovým uzávěrem; Pset_BuildingElementProxyCommon - ThermalTransmittance: 0.8 W/K/m2
 | Půdorys 1.NP | SDK - 1 KCE + DVOJITÉ OPLÁŠTĚNÍ | Suché stavební práce |  |  | SDK - 1 KCE + DVOJITÉ OPLÁŠTĚNÍ | 1464Zas1096313266 | m3 | Stěna | 1 | NEMSOK - Kód prvku: SN07.03.0001; Podlaží: 1.NP; Funkce (venkovní): Ne; 2D interakce: yes; Požární odolnost: EI 60; Vlhkostní namáhání oboustranné: Ne; Tloušťka opláštění: 2×12,5; Typ SDK desky: vysokopevnostní+bílá; Způsob opláštění: Oboustranné; Tloušťka izolace (2): 100; Objemová hmotnost izolace: 25; Typ profilu pro SDK: CW 100; Rozteč rastru: 625; Statická funkce: Ne; Vážená stavební neprůzvučnost: 54; Pset_BuildingElementProxyCommon - Status: NEW; LoadBearing: no
I.Z6 | Půdorys 1.NP |  |  | 0 | I.Z6 |  | 1464Obj1096313543 | Kus | Okno - objekt+SmartPart | 1 | NEMSOK - Verze programu: 2.2; Plugin_Bezeichnung: MainObject; Plugin_Objektname: SmartPartCompressed; Verze: 3.0; Jednotková_cena: 0; Uvažované procento prosklení: 100; Plocha_skla: 0; Výška_vnějšího_parapetu: 0 m; Výška_vnitřního_parapetu: 0 m; Odstup_od_otvoru_dole: 0 m; Odstup_od_otvoru_nahoře: 0 m; Odstup_od_otvoru_vlevo: 0 m; Odstup_od_otvoru_vpravo: 0 m; Tloušťka_zárubně/rámu_dole: 0.02 m; Tloušťka_zárubně/rámu_vlevo: 0.02 m; Tloušťka_zárubně/rámu_vpravo: 0.02 m; Tloušťka_zárubně/rámu_nahoře: 0.02 m; Ochrana proti kouři: no; Nouzový východ: no; Bezpečnostní třída: SA; Zárubeň/Rám_Typ: Dřevěný rám 92 mm; Zárubeň/Rám_Materiál: Dřevěný lepený eurohranol; Zárubeň/Rám_Povrch: Bílý lak; Křídlo_Materiál: Dřevěný lepený eurohranol; Křídlo_Povrch_Int.: Bílý lak; Křídlo_Povrch_Ext.: Bílý lak; Kování_Klika_Ext.: není; Kování_Zámek: není; Kování_Klika_Int.: Okenní klika; Specifikace: Bemerkung mit max 254Zeichen; Kování_Závěsy: Celoobvodové kování s pětibodovým uzávěrem; Pset_BuildingElementProxyCommon - ThermalTransmittance: 0.8 W/K/m2
I.Z6 | Půdorys 1.NP |  |  | 0 | I.Z6 |  | 1464Obj1096313549 | Kus | Okno - objekt+SmartPart | 1 | NEMSOK - Verze programu: 2.2; Plugin_Bezeichnung: MainObject; Plugin_Objektname: SmartPartCompressed; Verze: 3.0; Jednotková_cena: 0; Uvažované procento prosklení: 100; Plocha_skla: 0; Výška_vnějšího_parapetu: 0 m; Výška_vnitřního_parapetu: 0 m; Odstup_od_otvoru_dole: 0 m; Odstup_od_otvoru_nahoře: 0 m; Odstup_od_otvoru_vlevo: 0 m; Odstup_od_otvoru_vpravo: 0 m; Tloušťka_zárubně/rámu_dole: 0.02 m; Tloušťka_zárubně/rámu_vlevo: 0.02 m; Tloušťka_zárubně/rámu_vpravo: 0.02 m; Tloušťka_zárubně/rámu_nahoře: 0.02 m; Ochrana proti kouři: no; Nouzový východ: no; Bezpečnostní třída: SA; Zárubeň/Rám_Typ: Dřevěný rám 92 mm; Zárubeň/Rám_Materiál: Dřevěný lepený eurohranol; Zárubeň/Rám_Povrch: Bílý lak; Křídlo_Materiál: Dřevěný lepený eurohranol; Křídlo_Povrch_Int.: Bílý lak; Křídlo_Povrch_Ext.: Bílý lak; Kování_Klika_Ext.: není; Kování_Zámek: není; Kování_Klika_Int.: Okenní klika; Specifikace: Bemerkung mit max 254Zeichen; Kování_Závěsy: Celoobvodové kování s pětibodovým uzávěrem; Pset_BuildingElementProxyCommon - ThermalTransmittance: 0.8 W/K/m2
I.Z6 | Půdorys 1.NP |  |  | 0 | I.Z6 |  | 1464Obj1096313537 | Kus | Okno - objekt+SmartPart | 1 | NEMSOK - Verze programu: 2.2; Plugin_Bezeichnung: MainObject; Plugin_Objektname: SmartPartCompressed; Verze: 3.0; Jednotková_cena: 0; Uvažované procento prosklení: 100; Plocha_skla: 0; Výška_vnějšího_parapetu: 0 m; Výška_vnitřního_parapetu: 0 m; Odstup_od_otvoru_dole: 0 m; Odstup_od_otvoru_nahoře: 0 m; Odstup_od_otvoru_vlevo: 0 m; Odstup_od_otvoru_vpravo: 0 m; Tloušťka_zárubně/rámu_dole: 0.02 m; Tloušťka_zárubně/rámu_vlevo: 0.02 m; Tloušťka_zárubně/rámu_vpravo: 0.02 m; Tloušťka_zárubně/rámu_nahoře: 0.02 m; Ochrana proti kouři: no; Nouzový východ: no; Bezpečnostní třída: SA; Zárubeň/Rám_Typ: Dřevěný rám 92 mm; Zárubeň/Rám_Materiál: Dřevěný lepený eurohranol; Zárubeň/Rám_Povrch: Bílý lak; Křídlo_Materiál: Dřevěný lepený eurohranol; Křídlo_Povrch_Int.: Bílý lak; Křídlo_Povrch_Ext.: Bílý lak; Kování_Klika_Ext.: není; Kování_Zámek: není; Kování_Klika_Int.: Okenní klika; Specifikace: Bemerkung mit max 254Zeichen; Kování_Závěsy: Celoobvodové kování s pětibodovým uzávěrem; Pset_BuildingElementProxyCommon - ThermalTransmittance: 0.8 W/K/m2
 | Půdorys 1.NP | SDK - 1 KCE + DVOJITÉ OPLÁŠTĚNÍ | Suché stavební práce |  |  | SDK - 1 KCE + DVOJITÉ OPLÁŠTĚNÍ | 1464Zas1096313020 | m3 | Stěna | 1 | NEMSOK - Kód prvku: SN07.03.0001; Podlaží: 1.NP; Funkce (venkovní): Ne; 2D interakce: yes; Požární odolnost: EI 60; Vlhkostní namáhání oboustranné: Ne; Tloušťka opláštění: 2×12,5; Typ SDK desky: vysokopevnostní+bílá; Způsob opláštění: Oboustranné; Tloušťka izolace (2): 100; Objemová hmotnost izolace: 25; Typ profilu pro SDK: CW 100; Rozteč rastru: 625; Statická funkce: Ne; Vážená stavební neprůzvučnost: 54; Pset_BuildingElementProxyCommon - Status: NEW; LoadBearing: no
 | Půdorys 1.NP | SDK - 1 KCE + DVOJITÉ OPLÁŠTĚNÍ | Suché stavební práce |  |  | SDK - 1 KCE + DVOJITÉ OPLÁŠTĚNÍ | 1464Zas1096313275 | m3 | Stěna | 1 | NEMSOK - Kód prvku: SN07.03.0001; Podlaží: 1.NP; Funkce (venkovní): Ne; 2D interakce: yes; Požární odolnost: EI 60; Vlhkostní namáhání oboustranné: Ne; Tloušťka opláštění: 2×12,5; Typ SDK desky: vysokopevnostní+bílá; Způsob opláštění: Oboustranné; Tloušťka izolace (2): 100; Objemová hmotnost izolace: 25; Typ profilu pro SDK: CW 100; Rozteč rastru: 625; Statická funkce: Ne; Vážená stavební neprůzvučnost: 54; Pset_BuildingElementProxyCommon - Status: NEW; LoadBearing: no
 | Půdorys 1.NP | SDK - 1 KCE + DVOJITÉ OPLÁŠTĚNÍ | Suché stavební práce |  |  | SDK - 1 KCE + DVOJITÉ OPLÁŠTĚNÍ | 1464Zas1096313067 | m3 | Stěna | 1 | NEMSOK - Kód prvku: SN07.03.0001; Podlaží: 1.NP; Funkce (venkovní): Ne; 2D interakce: yes; Požární odolnost: EI 60; Vlhkostní namáhání oboustranné: Ne; Tloušťka opláštění: 2×12,5; Typ SDK desky: vysokopevnostní+bílá; Způsob opláštění: Oboustranné; Tloušťka izolace (2): 100; Objemová hmotnost izolace: 25; Typ profilu pro SDK: CW 100; Rozteč rastru: 625; Statická funkce: Ne; Vážená stavební neprůzvučnost: 54; Pset_BuildingElementProxyCommon - Status: NEW; LoadBearing: no
 | Půdorys 1.NP | SDK - 1 KCE + DVOJITÉ OPLÁŠTĚNÍ | Suché stavební práce |  |  | SDK - 1 KCE + DVOJITÉ OPLÁŠTĚNÍ | 1464Zas1096313656 | m3 | Stěna | 1 | NEMSOK - Kód prvku: SN07.03.0001; Podlaží: 1.NP; Funkce (venkovní): Ne; 2D interakce: yes; Požární odolnost: EI 60; Vlhkostní namáhání oboustranné: Ne; Tloušťka opláštění: 2×12,5; Typ SDK desky: vysokopevnostní+bílá; Způsob opláštění: Oboustranné; Tloušťka izolace (2): 100; Objemová hmotnost izolace: 25; Typ profilu pro SDK: CW 100; Rozteč rastru: 625; Statická funkce: Ne; Vážená stavební neprůzvučnost: 54; Pset_BuildingElementProxyCommon - Status: NEW; LoadBearing: no
 | Půdorys 1.NP | SDK - 1 KCE + DVOJITÉ OPLÁŠTĚNÍ | Suché stavební práce |  |  | SDK - 1 KCE + DVOJITÉ OPLÁŠTĚNÍ | 1464Zas1096313104 | m3 | Stěna | 1 | NEMSOK - Kód prvku: SN07.03.0001; Podlaží: 1.NP; Funkce (venkovní): Ne; 2D interakce: yes; Požární odolnost: EI 60; Vlhkostní namáhání oboustranné: Ne; Tloušťka opláštění: 2×12,5; Typ SDK desky: vysokopevnostní+bílá; Způsob opláštění: Oboustranné; Tloušťka izolace (2): 100; Objemová hmotnost izolace: 25; Typ profilu pro SDK: CW 100; Rozteč rastru: 625; Statická funkce: Ne; Vážená stavební neprůzvučnost: 54; Pset_BuildingElementProxyCommon - Status: NEW; LoadBearing: no
 | Půdorys 1.NP | SDK - 1 KCE + DVOJITÉ OPLÁŠTĚNÍ | Suché stavební práce |  |  | SDK - 1 KCE + DVOJITÉ OPLÁŠTĚNÍ | 1464Zas1096314010 | m3 | Stěna | 1 | NEMSOK - Kód prvku: SN07.03.0001; Podlaží: 1.NP; Funkce (venkovní): Ne; 2D interakce: yes; Požární odolnost: EI 60; Vlhkostní namáhání oboustranné: Ne; Tloušťka opláštění: 2×12,5; Typ SDK desky: vysokopevnostní+bílá; Způsob opláštění: Oboustranné; Tloušťka izolace (2): 100; Objemová hmotnost izolace: 25; Typ profilu pro SDK: CW 100; Rozteč rastru: 625; Statická funkce: Ne; Vážená stavební neprůzvučnost: 54; Pset_BuildingElementProxyCommon - Status: NEW; LoadBearing: no
 | Půdorys 1.NP | SDK - 1 KCE + DVOJITÉ OPLÁŠTĚNÍ | Suché stavební práce |  |  | SDK - 1 KCE + DVOJITÉ OPLÁŠTĚNÍ | 1464Zas1096313295 | m3 | Stěna | 1 | NEMSOK - Kód prvku: SN07.03.0001; Podlaží: 1.NP; Funkce (venkovní): Ne; 2D interakce: yes; Požární odolnost: EI 60; Vlhkostní namáhání oboustranné: Ne; Tloušťka opláštění: 2×12,5; Typ SDK desky: vysokopevnostní+bílá; Způsob opláštění: Oboustranné; Tloušťka izolace (2): 100; Objemová hmotnost izolace: 25; Typ profilu pro SDK: CW 100; Rozteč rastru: 625; Statická funkce: Ne; Vážená stavební neprůzvučnost: 54; Pset_BuildingElementProxyCommon - Status: NEW; LoadBearing: no
 | Půdorys 1.NP | SDK INSTAL. PŘDSTĚNA VYSOKÁ | Suché stavební práce |  |  | SDK INSTAL. PŘDSTĚNA VYSOKÁ | 1464Zas1096313451 | m3 | Stěna | 1 | NEMSOK - Kód prvku: SN07.03.0001; Podlaží: 1.NP; Funkce (venkovní): Ne; 2D interakce: yes; Požární odolnost: bez požadavku; Vlhkostní namáhání oboustranné: Ne; Tloušťka opláštění: 2×12,5; Typ SDK desky: impregnovaná; Způsob opláštění: Jednostranné; Tloušťka izolace (2): 0; Objemová hmotnost izolace: 0; Typ profilu pro SDK: CW 100; Rozteč rastru: 625; Statická funkce: Ne; Pset_BuildingElementProxyCommon - Status: NEW; LoadBearing: no
I.Z6 | Půdorys 1.NP |  |  | 0 | I.Z6 |  | 1464Obj1096313531 | Kus | Okno - objekt+SmartPart | 1 | NEMSOK - Verze programu: 2.2; Plugin_Bezeichnung: MainObject; Plugin_Objektname: SmartPartCompressed; Verze: 3.0; Jednotková_cena: 0; Uvažované procento prosklení: 100; Plocha_skla: 0; Výška_vnějšího_parapetu: 0 m; Výška_vnitřního_parapetu: 0 m; Odstup_od_otvoru_dole: 0 m; Odstup_od_otvoru_nahoře: 0 m; Odstup_od_otvoru_vlevo: 0 m; Odstup_od_otvoru_vpravo: 0 m; Tloušťka_zárubně/rámu_dole: 0.02 m; Tloušťka_zárubně/rámu_vlevo: 0.02 m; Tloušťka_zárubně/rámu_vpravo: 0.02 m; Tloušťka_zárubně/rámu_nahoře: 0.02 m; Ochrana proti kouři: no; Nouzový východ: no; Bezpečnostní třída: SA; Zárubeň/Rám_Typ: Dřevěný rám 92 mm; Zárubeň/Rám_Materiál: Dřevěný lepený eurohranol; Zárubeň/Rám_Povrch: Bílý lak; Křídlo_Materiál: Dřevěný lepený eurohranol; Křídlo_Povrch_Int.: Bílý lak; Křídlo_Povrch_Ext.: Bílý lak; Kování_Klika_Ext.: není; Kování_Zámek: není; Kování_Klika_Int.: Okenní klika; Specifikace: Bemerkung mit max 254Zeichen; Kování_Závěsy: Celoobvodové kování s pětibodovým uzávěrem; Pset_BuildingElementProxyCommon - ThermalTransmittance: 0.8 W/K/m2
 | Půdorys 1.NP |  |  |  |  |  | 1465ExE0000024645 | Kus | I.SŠ | 1
 | Půdorys 1.NP |  |  |  |  |  | 1465ExE0000024650 | Kus | I.SŠ | 1
 | Půdorys 1.NP |  |  |  |  |  | 1465ExE0000024655 | Kus | I.SŠ | 1
 | Půdorys 1.NP |  |  |  |  |  | 1465ExE0000024660 | Kus | I.SŠ | 1
 | Půdorys 1.NP |  |  |  |  |  | 1465ExE0000024665 | Kus | I.SŠ | 1
 | Půdorys 1.NP |  |  |  |  |  | 1465ExE0000024670 | Kus | I.SŠ | 1
 | Půdorys 1.NP |  |  |  |  |  | 1465ExE0000024675 | Kus | I.SŠ | 1
 | Půdorys 1.NP |  |  |  |  |  | 1465ExE0000024680 | Kus | I.SŠ | 1
 | Půdorys 1.NP |  |  |  |  |  | 1465ExE0000024685 | Kus | I.SŠ | 1
 | Půdorys 1.NP |  |  |  |  |  | 1465ExE0000024690 | Kus | I.SŠ | 1
 | Půdorys 1.NP |  |  |  |  |  | 1465ExE0000024695 | Kus | I.SŠ | 1
 | Půdorys 1.NP |  |  |  |  |  | 1465ExE0000024700 | Kus | I.SŠ | 1
 | Půdorys 1.NP |  |  |  |  |  | 1465ExE0000024705 | Kus | I.SŠ | 1
 | Půdorys 1.NP |  |  |  |  |  | 1465ExE0000024710 | Kus | I.SŠ | 1
 | Půdorys 1.NP |  |  |  |  |  | 1465ExE0000024715 | Kus | I.SŠ | 1
 | Půdorys 1.NP |  |  |  |  |  | 1465ExE0000024625 | Kus | I.SŠ | 1
 | Půdorys 1.NP |  |  |  |  |  | 1465ExE0000024620 | Kus | I.SŠ | 1
 | Půdorys 1.NP |  |  |  |  |  | 1465ExE0000024615 | Kus | I.SŠ | 1
 | Půdorys 1.NP |  |  |  |  |  | 1465ExE0000024610 | Kus | I.SŠ | 1
 | Půdorys 1.NP |  |  |  |  |  | 1465ExE0000024605 | Kus | I.SŠ | 1
 | Půdorys 1.NP |  |  |  |  |  | 1465ExE0000024593 | Kus | I.SŠ | 1
 | Půdorys 1.NP |  |  |  |  |  | 1465ExE0000024640 | Kus | II.SŠ | 1
 | Půdorys 1.NP |  |  |  |  |  | 1465ExE0000024635 | Kus | II.SŠ | 1
Parapet vnější | Půdorys 2.NP | PLECH | Klempířské práce | 0 | Parapet vnější | PLECH | 1552Obj0798439714 | m | Parapet - objekt+SmartPart | 1 | NEMSOK - Absolutní_výška: 0.03 m; Tloušťka: 0.1 m; Výška: 0.005 m; Objem: 0.0012505; Plocha: 0.2156; Poloha (vnitřní/venkovní): 1
Parapet vnější | Půdorys 2.NP | PLECH | Klempířské práce | 0 | Parapet vnější | PLECH | 1552Obj0798439776 | m | Parapet - objekt+SmartPart | 1 | NEMSOK - Absolutní_výška: 0.03 m; Tloušťka: 0.1 m; Výška: 0.005 m; Objem: 0.0012505; Plocha: 0.2156; Poloha (vnitřní/venkovní): 1
Ocelový profil | Půdorys 2.NP | U 140 |  | 0 | Ocelový profil | U 140 | 1552Sma0000001478 | Kus | SmartPart | 1 | NEMSOK - Verze programu: 1.0; Plugin_Bezeichnung: MainObject; Plugin_Objektname: SmartPartCompressed; Verze: 1.0; Dolní_hrana: 0 m; Horní_hrana: 0 m
Ocelový profil | Půdorys 2.NP | U 140 |  | 0 | Ocelový profil | U 140 | 1552Sma0000001477 | Kus | SmartPart | 1 | NEMSOK - Verze programu: 1.0; Plugin_Bezeichnung: MainObject; Plugin_Objektname: SmartPartCompressed; Verze: 1.0; Dolní_hrana: 0 m; Horní_hrana: 0 m
Parapet vnější | Půdorys 2.NP | PLECH | Klempířské práce | 0 | Parapet vnější | PLECH | 1552Obj0798440214 | m | Parapet - objekt+SmartPart | 1 | NEMSOK - Absolutní_výška: 0.03 m; Tloušťka: 0.1 m; Výška: 0.005 m; Objem: 0.0012505; Plocha: 0.2156; Poloha (vnitřní/venkovní): 1
Parapet vnější | Půdorys 2.NP | PLECH | Klempířské práce | 0 | Parapet vnější | PLECH | 1552Obj0798440291 | m | Parapet - objekt+SmartPart | 1 | NEMSOK - Absolutní_výška: 0.03 m; Tloušťka: 0.1 m; Výška: 0.005 m; Objem: 0.0012505; Plocha: 0.2156; Poloha (vnitřní/venkovní): 1
Parapet vnější | Půdorys 2.NP | PLECH | Klempířské práce | 0 | Parapet vnější | PLECH | 1552Obj0798440282 | m | Parapet - objekt+SmartPart | 1 | NEMSOK - Absolutní_výška: 0.03 m; Tloušťka: 0.1 m; Výška: 0.005 m; Objem: 0.0012505; Plocha: 0.2156; Poloha (vnitřní/venkovní): 1
Parapet vnější | Půdorys 2.NP | PLECH | Klempířské práce | 0 | Parapet vnější | PLECH | 1552Obj0798440273 | m | Parapet - objekt+SmartPart | 1 | NEMSOK - Absolutní_výška: 0.03 m; Tloušťka: 0.1 m; Výška: 0.005 m; Objem: 0.0012505; Plocha: 0.2156; Poloha (vnitřní/venkovní): 1
Parapet vnější | Půdorys 2.NP | PLECH | Klempířské práce | 0 | Parapet vnější | PLECH | 1552Obj0798440264 | m | Parapet - objekt+SmartPart | 1 | NEMSOK - Absolutní_výška: 0.03 m; Tloušťka: 0.1 m; Výška: 0.005 m; Objem: 0.0012505; Plocha: 0.2156; Poloha (vnitřní/venkovní): 1
Parapet vnější | Půdorys 2.NP | PLECH | Klempířské práce | 0 | Parapet vnější | PLECH | 1552Obj0798440255 | m | Parapet - objekt+SmartPart | 1 | NEMSOK - Absolutní_výška: 0.03 m; Tloušťka: 0.1 m; Výška: 0.005 m; Objem: 0.0012505; Plocha: 0.2156; Poloha (vnitřní/venkovní): 1
Parapet vnější | Půdorys 2.NP | PLECH | Klempířské práce | 0 | Parapet vnější | PLECH | 1552Obj0798440246 | m | Parapet - objekt+SmartPart | 1 | NEMSOK - Absolutní_výška: 0.03 m; Tloušťka: 0.1 m; Výška: 0.005 m; Objem: 0.0012505; Plocha: 0.2156; Poloha (vnitřní/venkovní): 1
Parapet vnější | Půdorys 2.NP | PLECH | Klempířské práce | 0 | Parapet vnější | PLECH | 1552Obj0798440237 | m | Parapet - objekt+SmartPart | 1 | NEMSOK - Absolutní_výška: 0.03 m; Tloušťka: 0.1 m; Výška: 0.005 m; Objem: 0.0012505; Plocha: 0.2156; Poloha (vnitřní/venkovní): 1
Parapet vnější | Půdorys 2.NP | PLECH | Klempířské práce | 0 | Parapet vnější | PLECH | 1552Obj0798437533 | m | Parapet - objekt+SmartPart | 1 | NEMSOK - Absolutní_výška: 0.03 m; Tloušťka: 0.1 m; Výška: 0.005 m; Objem: 0.0012505; Plocha: 0.2156; Poloha (vnitřní/venkovní): 1
Parapet vnější | Půdorys 2.NP | PLECH | Klempířské práce | 0 | Parapet vnější | PLECH | 1552Obj0798438866 | m | Parapet - objekt+SmartPart | 1 | NEMSOK - Absolutní_výška: 0.03 m; Tloušťka: 0.1 m; Výška: 0.005 m; Objem: 0.0012505; Plocha: 0.2156; Poloha (vnitřní/venkovní): 1
Parapet vnější | Půdorys 2.NP | PLECH | Klempířské práce | 0 | Parapet vnější | PLECH | 1552Obj0798438898 | m | Parapet - objekt+SmartPart | 1 | NEMSOK - Absolutní_výška: 0.03 m; Tloušťka: 0.1 m; Výška: 0.005 m; Objem: 0.0012505; Plocha: 0.2156; Poloha (vnitřní/venkovní): 1
Parapet vnější | Půdorys 2.NP | PLECH | Klempířské práce | 0 | Parapet vnější | PLECH | 1552Obj0798438889 | m | Parapet - objekt+SmartPart | 1 | NEMSOK - Absolutní_výška: 0.03 m; Tloušťka: 0.1 m; Výška: 0.005 m; Objem: 0.0012505; Plocha: 0.2156; Poloha (vnitřní/venkovní): 1
Parapet vnější | Půdorys 2.NP | PLECH | Klempířské práce | 0 | Parapet vnější | PLECH | 1552Obj0798437029 | m | Parapet - objekt+SmartPart | 1 | NEMSOK - Absolutní_výška: 0.03 m; Tloušťka: 0.1 m; Výška: 0.005 m; Objem: 0.0012505; Plocha: 0.2156; Poloha (vnitřní/venkovní): 1
Parapet vnější | Půdorys 2.NP | PLECH | Klempířské práce | 0 | Parapet vnější | PLECH | 1552Obj0798437016 | m | Parapet - objekt+SmartPart | 1 | NEMSOK - Absolutní_výška: 0.03 m; Tloušťka: 0.1 m; Výška: 0.005 m; Objem: 0.0012505; Plocha: 0.2156; Poloha (vnitřní/venkovní): 1
Parapet vnější | Půdorys 2.NP | PLECH | Klempířské práce | 0 | Parapet vnější | PLECH | 1552Obj0798437003 | m | Parapet - objekt+SmartPart | 1 | NEMSOK - Absolutní_výška: 0.03 m; Tloušťka: 0.1 m; Výška: 0.005 m; Objem: 0.0012505; Plocha: 0.2156; Poloha (vnitřní/venkovní): 1
Parapet vnější | Půdorys 2.NP | PLECH | Klempířské práce | 0 | Parapet vnější | PLECH | 1552Obj0798437453 | m | Parapet - objekt+SmartPart | 1 | NEMSOK - Absolutní_výška: 0.03 m; Tloušťka: 0.1 m; Výška: 0.005 m; Objem: 0.0012505; Plocha: 0.2156; Poloha (vnitřní/venkovní): 1
Parapet vnější | Půdorys 2.NP | PLECH | Klempířské práce | 0 | Parapet vnější | PLECH | 1552Obj0798437379 | m | Parapet - objekt+SmartPart | 1 | NEMSOK - Absolutní_výška: 0.03 m; Tloušťka: 0.1 m; Výška: 0.005 m; Objem: 0.0012505; Plocha: 0.2156; Poloha (vnitřní/venkovní): 1
Parapet vnější | Půdorys 2.NP | PLECH | Klempířské práce | 0 | Parapet vnější | PLECH | 1552Obj0798437339 | m | Parapet - objekt+SmartPart | 1 | NEMSOK - Absolutní_výška: 0.03 m; Tloušťka: 0.1 m; Výška: 0.005 m; Objem: 0.0012505; Plocha: 0.2156; Poloha (vnitřní/venkovní): 1
Parapet vnější | Půdorys 2.NP | PLECH | Klempířské práce | 0 | Parapet vnější | PLECH | 1552Obj0798437265 | m | Parapet - objekt+SmartPart | 1 | NEMSOK - Absolutní_výška: 0.03 m; Tloušťka: 0.1 m; Výška: 0.005 m; Objem: 0.001003; Plocha: 0.1736; Poloha (vnitřní/venkovní): 1
Parapet vnější | Půdorys 2.NP | PLECH | Klempířské práce | 0 | Parapet vnější | PLECH | 1552Obj0798437225 | m | Parapet - objekt+SmartPart | 1 | NEMSOK - Absolutní_výška: 0.03 m; Tloušťka: 0.1 m; Výška: 0.005 m; Objem: 0.001003; Plocha: 0.1736; Poloha (vnitřní/venkovní): 1
Parapet vnější | Půdorys 2.NP | PLECH | Klempířské práce | 0 | Parapet vnější | PLECH | 1552Obj0798437185 | m | Parapet - objekt+SmartPart | 1 | NEMSOK - Absolutní_výška: 0.03 m; Tloušťka: 0.1 m; Výška: 0.005 m; Objem: 0.001003; Plocha: 0.1736; Poloha (vnitřní/venkovní): 1
Parapet vnější | Půdorys 2.NP | PLECH | Klempířské práce | 0 | Parapet vnější | PLECH | 1552Obj0798437129 | m | Parapet - objekt+SmartPart | 1 | NEMSOK - Absolutní_výška: 0.03 m; Tloušťka: 0.1 m; Výška: 0.005 m; Objem: 0.001003; Plocha: 0.1736; Poloha (vnitřní/venkovní): 1
Parapet vnější | Půdorys 2.NP | PLECH | Klempířské práce | 0 | Parapet vnější | PLECH | 1552Obj0798440921 | m | Parapet - objekt+SmartPart | 1 | NEMSOK - Absolutní_výška: 0.03 m; Tloušťka: 0.1 m; Výška: 0.005 m; Objem: 0.0012505; Plocha: 0.2156; Poloha (vnitřní/venkovní): 1
Parapet vnější | Půdorys 2.NP | PLECH | Klempířské práce | 0 | Parapet vnější | PLECH | 1552Obj0798440985 | m | Parapet - objekt+SmartPart | 1 | NEMSOK - Absolutní_výška: 0.03 m; Tloušťka: 0.1 m; Výška: 0.005 m; Objem: 0.0012505; Plocha: 0.2156; Poloha (vnitřní/venkovní): 1
Parapet vnější | Půdorys 2.NP | PLECH | Klempířské práce | 0 | Parapet vnější | PLECH | 1552Obj0798441009 | m | Parapet - objekt+SmartPart | 1 | NEMSOK - Absolutní_výška: 0.03 m; Tloušťka: 0.1 m; Výška: 0.005 m; Objem: 0.001003; Plocha: 0.1736; Poloha (vnitřní/venkovní): 1
Parapet vnější | Půdorys 2.NP | PLECH | Klempířské práce | 0 | Parapet vnější | PLECH | 1552Obj0798440449 | m | Parapet - objekt+SmartPart | 1 | NEMSOK - Absolutní_výška: 0.03 m; Tloušťka: 0.1 m; Výška: 0.005 m; Objem: 0.001993; Plocha: 0.3416; Poloha (vnitřní/venkovní): 1
Parapet vnější | Půdorys 2.NP | PLECH | Klempířské práce | 0 | Parapet vnější | PLECH | 1552Obj0798440511 | m | Parapet - objekt+SmartPart | 1 | NEMSOK - Absolutní_výška: 0.03 m; Tloušťka: 0.1 m; Výška: 0.005 m; Objem: 0.001993; Plocha: 0.3416; Poloha (vnitřní/venkovní): 1
Parapet vnější | Půdorys 2.NP | PLECH | Klempířské práce | 0 | Parapet vnější | PLECH | 1552Obj0798440552 | m | Parapet - objekt+SmartPart | 1 | NEMSOK - Absolutní_výška: 0.03 m; Tloušťka: 0.1 m; Výška: 0.005 m; Objem: 0.0012505; Plocha: 0.2156; Poloha (vnitřní/venkovní): 1
Parapet vnější | Půdorys 2.NP | PLECH | Klempířské práce | 0 | Parapet vnější | PLECH | 1552Obj0798440543 | m | Parapet - objekt+SmartPart | 1 | NEMSOK - Absolutní_výška: 0.03 m; Tloušťka: 0.1 m; Výška: 0.005 m; Objem: 0.0012505; Plocha: 0.2156; Poloha (vnitřní/venkovní): 1
Parapet vnější | Půdorys 2.NP | PLECH | Klempířské práce | 0 | Parapet vnější | PLECH | 1552Obj0798440534 | m | Parapet - objekt+SmartPart | 1 | NEMSOK - Absolutní_výška: 0.03 m; Tloušťka: 0.1 m; Výška: 0.005 m; Objem: 0.0012505; Plocha: 0.2156; Poloha (vnitřní/venkovní): 1
f | Půdorys 2.NP | PLECH | Klempířské práce | 0 | f | PLECH | 1552Obj0798440657 | m | Parapet - objekt+SmartPart | 1 | NEMSOK - Absolutní_výška: 0.03 m; Tloušťka: 0.1 m; Výška: 0.005 m; Objem: 0.000508; Plocha: 0.0896; Poloha (vnitřní/venkovní): 1
f | Půdorys 2.NP | PLECH | Klempířské práce | 0 | f | PLECH | 1552Obj0798440698 | m | Parapet - objekt+SmartPart | 1 | NEMSOK - Absolutní_výška: 0.03 m; Tloušťka: 0.1 m; Výška: 0.005 m; Objem: 0.000508; Plocha: 0.0896; Poloha (vnitřní/venkovní): 1
f | Půdorys 2.NP | PLECH | Klempířské práce | 0 | f | PLECH | 1552Obj0798440689 | m | Parapet - objekt+SmartPart | 1 | NEMSOK - Absolutní_výška: 0.03 m; Tloušťka: 0.1 m; Výška: 0.005 m; Objem: 0.000508; Plocha: 0.0896; Poloha (vnitřní/venkovní): 1
f | Půdorys 2.NP | PLECH | Klempířské práce | 0 | f | PLECH | 1552Obj0798440680 | m | Parapet - objekt+SmartPart | 1 | NEMSOK - Absolutní_výška: 0.03 m; Tloušťka: 0.1 m; Výška: 0.005 m; Objem: 0.000508; Plocha: 0.0896; Poloha (vnitřní/venkovní): 1
 | Půdorys 2.NP | EPS | Zateplovací systémy |  |  | EPS | 1552Zas0798450636 | m2 | Zaslepení | 1
ŽEBŘÍK PŘES ATIKU | Půdorys 2.NP |  |  | 0 | ŽEBŘÍK PŘES ATIKU |  | 1564Obj0798475668 | Kus | II.Z3.1 | 1 | NEMSOK - Kód prvku: ZV00.04.3001
ŽEBŘÍK PŘES ATIKU | Půdorys 2.NP |  |  | 0 | ŽEBŘÍK PŘES ATIKU |  | 1564Obj0798475837 | Kus | II.Z3.2 | 1 | NEMSOK - Kód prvku: ZV00.04.3002
Parapet vnější | Půdorys 2.NP | HLINÍKOVÝ PLECH ELOXOVANÝ | Klempířské práce | 0 | Parapet vnější | HLINÍKOVÝ PLECH ELOXOVANÝ | 1564Obj0798450809 | m | II.K1 | 1 | NEMSOK - Absolutní_výška: 0.03 m; Tloušťka: 0.05 m; Výška: 0.005 m; Poloha (vnitřní/venkovní): 1; Kód prvku: KV01.04.0001; Podlaží: 2.NP; Rozvinutá šířka: 0.32 m; Pset_BuildingElementProxyCommon - Status: NEW
Parapet vnější | Půdorys 2.NP | HLINÍKOVÝ PLECH ELOXOVANÝ | Klempířské práce | 0 | Parapet vnější | HLINÍKOVÝ PLECH ELOXOVANÝ | 1564Obj0798469828 | m | Parapet - objekt+SmartPart | 1 | NEMSOK - Absolutní_výška: 0.03 m; Tloušťka: 0.1 m; Výška: 0.005 m; Objem: 0.0012505; Plocha: 0.2156; Poloha (vnitřní/venkovní): 1; Kód prvku: ON04.04.0001; Podlaží: 2.NP; Rozvinutá šířka: 0.22 m; Pset_BuildingElementProxyCommon - Status: NEW
Parapet vnější | Půdorys 2.NP | HLINÍKOVÝ PLECH ELOXOVANÝ | Klempířské práce | 0 | Parapet vnější | HLINÍKOVÝ PLECH ELOXOVANÝ | 1564Obj0798470800 | m | Parapet - objekt+SmartPart | 1 | NEMSOK - Absolutní_výška: 0.03 m; Tloušťka: 0.1 m; Výška: 0.005 m; Objem: 0.002323; Plocha: 0.3976; Poloha (vnitřní/venkovní): 1; Kód prvku: ON04.04.0002; Podlaží: 2.NP; Rozvinutá šířka: 0.22 m; Pset_BuildingElementProxyCommon - Status: NEW
Parapet vnější | Půdorys 3.NP | PLECH | Klempířské práce | 0 | Parapet vnější | PLECH | 1652Obj0798439699 | m | Parapet - objekt+SmartPart | 1 | NEMSOK - Absolutní_výška: 0.03 m; Tloušťka: 0.1 m; Výška: 0.005 m; Objem: 0.0012505; Plocha: 0.2156; Poloha (vnitřní/venkovní): 1
Parapet vnější | Půdorys 3.NP | PLECH | Klempířské práce | 0 | Parapet vnější | PLECH | 1652Obj0798439722 | m | Parapet - objekt+SmartPart | 1 | NEMSOK - Absolutní_výška: 0.03 m; Tloušťka: 0.1 m; Výška: 0.005 m; Objem: 0.0012505; Plocha: 0.2156; Poloha (vnitřní/venkovní): 1
Parapet vnější | Půdorys 3.NP | PLECH | Klempířské práce | 0 | Parapet vnější | PLECH | 1652Obj0798439745 | m | Parapet - objekt+SmartPart | 1 | NEMSOK - Absolutní_výška: 0.03 m; Tloušťka: 0.1 m; Výška: 0.005 m; Objem: 0.0012505; Plocha: 0.2156; Poloha (vnitřní/venkovní): 1
Parapet vnější | Půdorys 3.NP | PLECH | Klempířské práce | 0 | Parapet vnější | PLECH | 1652Obj0798426671 | m | Parapet - objekt+SmartPart | 1 | NEMSOK - Absolutní_výška: 0.03 m; Tloušťka: 0.1 m; Výška: 0.005 m; Objem: 0.0012505; Plocha: 0.2156; Poloha (vnitřní/venkovní): 1
Parapet vnější | Půdorys 3.NP | PLECH | Klempířské práce | 0 | Parapet vnější | PLECH | 1652Obj0798436348 | m | Parapet - objekt+SmartPart | 1 | NEMSOK - Absolutní_výška: 0.03 m; Tloušťka: 0.1 m; Výška: 0.005 m; Objem: 0.0012505; Plocha: 0.2156; Poloha (vnitřní/venkovní): 1
Parapet vnější | Půdorys 3.NP | PLECH | Klempířské práce | 0 | Parapet vnější | PLECH | 1652Obj0798436359 | m | Parapet - objekt+SmartPart | 1 | NEMSOK - Absolutní_výška: 0.03 m; Tloušťka: 0.1 m; Výška: 0.005 m; Objem: 0.0012505; Plocha: 0.2156; Poloha (vnitřní/venkovní): 1
Parapet vnější | Půdorys 3.NP | PLECH | Klempířské práce | 0 | Parapet vnější | PLECH | 1652Obj0798439167 | m | Parapet - objekt+SmartPart | 1 | NEMSOK - Absolutní_výška: 0.03 m; Tloušťka: 0.1 m; Výška: 0.005 m; Objem: 0.0012505; Plocha: 0.2156; Poloha (vnitřní/venkovní): 1
Parapet vnější | Půdorys 3.NP | PLECH | Klempířské práce | 0 | Parapet vnější | PLECH | 1652Obj0798431752 | m | Parapet - objekt+SmartPart | 1 | NEMSOK - Absolutní_výška: 0.03 m; Tloušťka: 0.16 m; Výška: 0.005 m; Objem: 0.0017005; Plocha: 0.308; Poloha (vnitřní/venkovní): 1
Parapet vnější | Půdorys 3.NP | PLECH | Klempířské práce | 0 | Parapet vnější | PLECH | 1652Obj0798439247 | m | Parapet - objekt+SmartPart | 1 | NEMSOK - Absolutní_výška: 0.03 m; Tloušťka: 0.1 m; Výška: 0.005 m; Objem: 0.0012505; Plocha: 0.2156; Poloha (vnitřní/venkovní): 1
Parapet vnější | Půdorys 3.NP | PLECH | Klempířské práce | 0 | Parapet vnější | PLECH | 1652Obj0798439314 | m | Parapet - objekt+SmartPart | 1 | NEMSOK - Absolutní_výška: 0.03 m; Tloušťka: 0.1 m; Výška: 0.005 m; Objem: 0.0012505; Plocha: 0.2156; Poloha (vnitřní/venkovní): 1
Parapet vnější | Půdorys 3.NP | PLECH | Klempířské práce | 0 | Parapet vnější | PLECH | 1652Obj0798439770 | m | Parapet - objekt+SmartPart | 1 | NEMSOK - Absolutní_výška: 0.03 m; Tloušťka: 0.1 m; Výška: 0.005 m; Objem: 0.0012505; Plocha: 0.2156; Poloha (vnitřní/venkovní): 1
Parapet vnější | Půdorys 3.NP | PLECH | Klempířské práce | 0 | Parapet vnější | PLECH | 1652Obj0798439793 | m | Parapet - objekt+SmartPart | 1 | NEMSOK - Absolutní_výška: 0.03 m; Tloušťka: 0.1 m; Výška: 0.005 m; Objem: 0.0012505; Plocha: 0.2156; Poloha (vnitřní/venkovní): 1
Ocelový profil | Půdorys 3.NP | U 140 |  | 0 | Ocelový profil | U 140 | 1652Sma0798421428 | Kus | SmartPart | 1 | NEMSOK - Verze programu: 1.0; Plugin_Bezeichnung: MainObject; Plugin_Objektname: SmartPartCompressed; Verze: 1.0; Dolní_hrana: 0 m; Horní_hrana: 0 m
Ocelový profil | Půdorys 3.NP | U 140 |  | 0 | Ocelový profil | U 140 | 1652Sma0798421438 | Kus | SmartPart | 1 | NEMSOK - Verze programu: 1.0; Plugin_Bezeichnung: MainObject; Plugin_Objektname: SmartPartCompressed; Verze: 1.0; Dolní_hrana: 0 m; Horní_hrana: 0 m
Parapet vnější | Půdorys 3.NP | PLECH | Klempířské práce | 0 | Parapet vnější | PLECH | 1652Obj0798437907 | m | Parapet - objekt+SmartPart | 1 | NEMSOK - Absolutní_výška: 0.03 m; Tloušťka: 0.1 m; Výška: 0.005 m; Objem: 0.001003; Plocha: 0.1736; Poloha (vnitřní/venkovní): 1
Parapet vnější | Půdorys 3.NP | PLECH | Klempířské práce | 0 | Parapet vnější | PLECH | 1652Obj0798437916 | m | Parapet - objekt+SmartPart | 1 | NEMSOK - Absolutní_výška: 0.03 m; Tloušťka: 0.1 m; Výška: 0.005 m; Objem: 0.001003; Plocha: 0.1736; Poloha (vnitřní/venkovní): 1
Parapet vnější | Půdorys 3.NP | PLECH | Klempířské práce | 0 | Parapet vnější | PLECH | 1652Obj0798437925 | m | Parapet - objekt+SmartPart | 1 | NEMSOK - Absolutní_výška: 0.03 m; Tloušťka: 0.1 m; Výška: 0.005 m; Objem: 0.001003; Plocha: 0.1736; Poloha (vnitřní/venkovní): 1
Parapet vnější | Půdorys 3.NP | PLECH | Klempířské práce | 0 | Parapet vnější | PLECH | 1652Obj0798437934 | m | Parapet - objekt+SmartPart | 1 | NEMSOK - Absolutní_výška: 0.03 m; Tloušťka: 0.1 m; Výška: 0.005 m; Objem: 0.001003; Plocha: 0.1736; Poloha (vnitřní/venkovní): 1
Parapet vnější | Půdorys 3.NP | PLECH | Klempířské práce | 0 | Parapet vnější | PLECH | 1652Obj0798437974 | m | Parapet - objekt+SmartPart | 1 | NEMSOK - Absolutní_výška: 0.03 m; Tloušťka: 0.1 m; Výška: 0.005 m; Objem: 0.0012505; Plocha: 0.2156; Poloha (vnitřní/venkovní): 1
Parapet vnější | Půdorys 3.NP | PLECH | Klempířské práce | 0 | Parapet vnější | PLECH | 1652Obj0798437983 | m | Parapet - objekt+SmartPart | 1 | NEMSOK - Absolutní_výška: 0.03 m; Tloušťka: 0.1 m; Výška: 0.005 m; Objem: 0.0012505; Plocha: 0.2156; Poloha (vnitřní/venkovní): 1
Parapet vnější | Půdorys 3.NP | PLECH | Klempířské práce | 0 | Parapet vnější | PLECH | 1652Obj0798437992 | m | Parapet - objekt+SmartPart | 1 | NEMSOK - Absolutní_výška: 0.03 m; Tloušťka: 0.1 m; Výška: 0.005 m; Objem: 0.0012505; Plocha: 0.2156; Poloha (vnitřní/venkovní): 1
Parapet vnější | Půdorys 3.NP | PLECH | Klempířské práce | 0 | Parapet vnější | PLECH | 1652Obj0798438001 | m | Parapet - objekt+SmartPart | 1 | NEMSOK - Absolutní_výška: 0.03 m; Tloušťka: 0.1 m; Výška: 0.005 m; Objem: 0.0012505; Plocha: 0.2156; Poloha (vnitřní/venkovní): 1
Parapet vnější | Půdorys 3.NP | PLECH | Klempířské práce | 0 | Parapet vnější | PLECH | 1652Obj0798438010 | m | Parapet - objekt+SmartPart | 1 | NEMSOK - Absolutní_výška: 0.03 m; Tloušťka: 0.1 m; Výška: 0.005 m; Objem: 0.0012505; Plocha: 0.2156; Poloha (vnitřní/venkovní): 1
Parapet vnější | Půdorys 3.NP | PLECH | Klempířské práce | 0 | Parapet vnější | PLECH | 1652Obj0798438019 | m | Parapet - objekt+SmartPart | 1 | NEMSOK - Absolutní_výška: 0.03 m; Tloušťka: 0.1 m; Výška: 0.005 m; Objem: 0.0012505; Plocha: 0.2156; Poloha (vnitřní/venkovní): 1
Parapet vnější | Půdorys 3.NP | PLECH | Klempířské práce | 0 | Parapet vnější | PLECH | 1652Obj0798438028 | m | Parapet - objekt+SmartPart | 1 | NEMSOK - Absolutní_výška: 0.03 m; Tloušťka: 0.1 m; Výška: 0.005 m; Objem: 0.001003; Plocha: 0.1736; Poloha (vnitřní/venkovní): 1
Parapet vnější | Půdorys 3.NP | PLECH | Klempířské práce | 0 | Parapet vnější | PLECH | 1652Obj0798438037 | m | Parapet - objekt+SmartPart | 1 | NEMSOK - Absolutní_výška: 0.03 m; Tloušťka: 0.1 m; Výška: 0.005 m; Objem: 0.001003; Plocha: 0.1736; Poloha (vnitřní/venkovní): 1
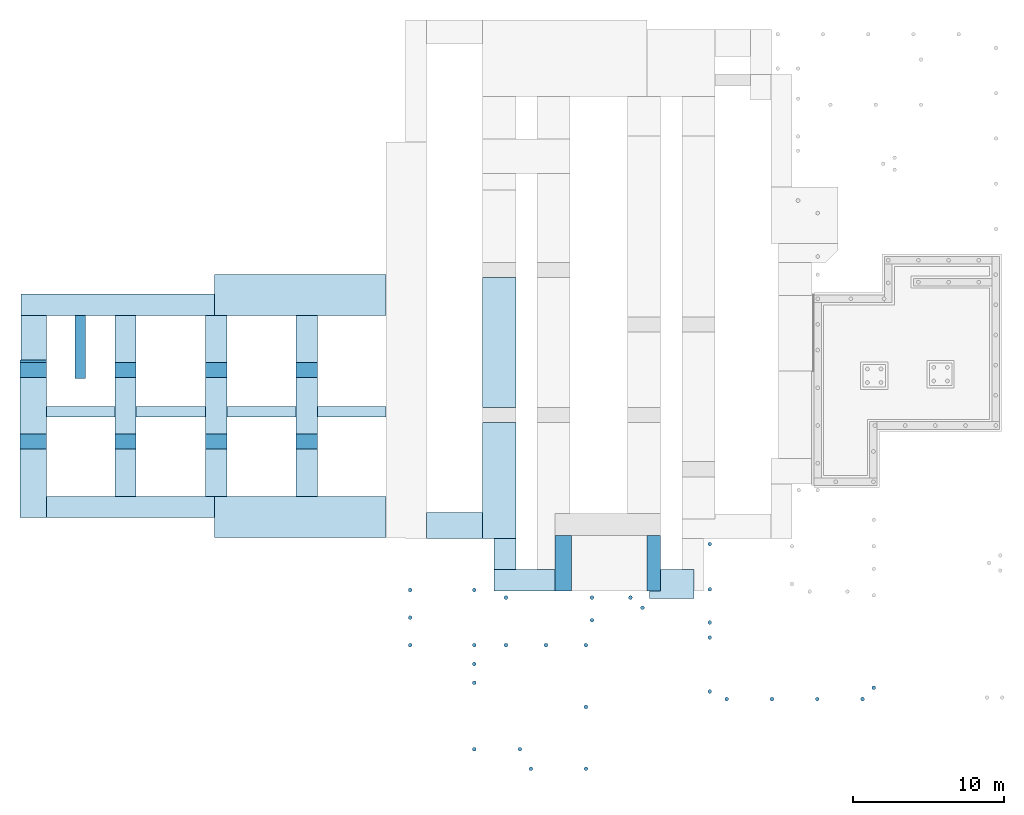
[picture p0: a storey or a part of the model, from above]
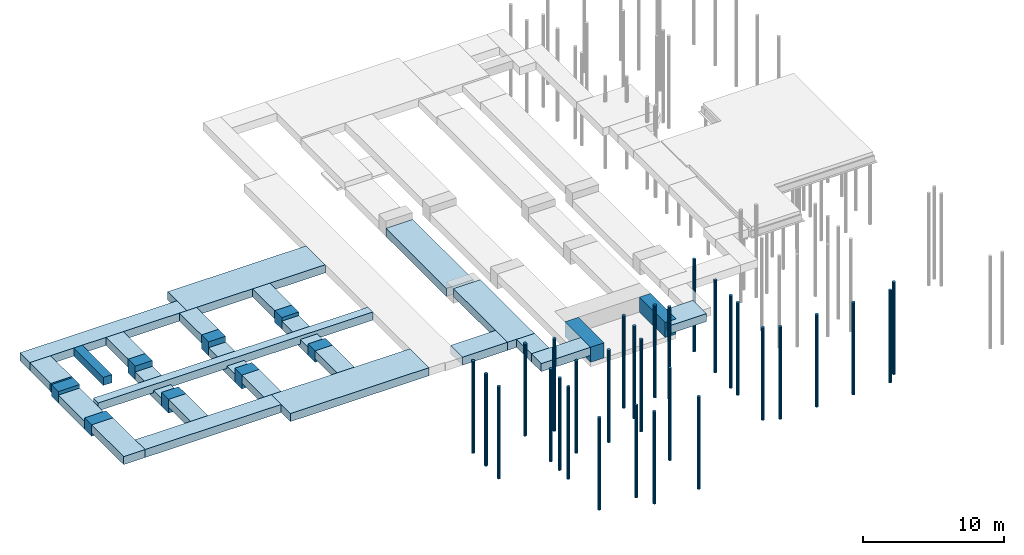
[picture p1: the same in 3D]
Properties of the parts of a building model (IFC4), part 3 of 45

# IfcBuildingElementProxy (404)
Name | In | Material | Práce | V6 (m) = V7 (m) = V8 (m) = V9 | Označení | Materiál | Allright_Stavebni_dil_ID | Jednotka | Název_objektu | NetSurfaceArea = NetVolume
Parapet vnější | Půdorys 3.NP | PLECH | Klempířské práce | 0 | Parapet vnější | PLECH | 1652Obj0798438046 | m | Parapet - objekt+SmartPart | 1 | NEMSOK - Absolutní_výška: 0.03 m; Tloušťka: 0.1 m; Výška: 0.005 m; Objem: 0.001003; Plocha: 0.1736; Poloha (vnitřní/venkovní): 1
Parapet vnější | Půdorys 3.NP | PLECH | Klempířské práce | 0 | Parapet vnější | PLECH | 1652Obj0798438055 | m | Parapet - objekt+SmartPart | 1 | NEMSOK - Absolutní_výška: 0.03 m; Tloušťka: 0.1 m; Výška: 0.005 m; Objem: 0.001003; Plocha: 0.1736; Poloha (vnitřní/venkovní): 1
O06 | Půdorys 3.NP |  |  | 0 | O06 |  | 1652Obj0798436064 | Kus | Okno - objekt+SmartPart | 1 | NEMSOK - Verze programu: 2.2; Plugin_Bezeichnung: MainObject; Plugin_Objektname: SmartPartCompressed; Verze: 3.0; Dolní_hrana: 0 m; Horní_hrana: 0 m; Jednotková_cena: 0; Uvažované procento prosklení: 100; Plocha_skla: 1.9344; Výška_vnějšího_parapetu: 0 m; Výška_vnitřního_parapetu: 0 m; Odstup_od_otvoru_dole: 0 m; Odstup_od_otvoru_nahoře: 0 m; Odstup_od_otvoru_vlevo: 0 m; Odstup_od_otvoru_vpravo: 0 m; Tloušťka_zárubně/rámu_dole: 0.08 m; Tloušťka_zárubně/rámu_vlevo: 0.08 m; Tloušťka_zárubně/rámu_vpravo: 0.08 m; Tloušťka_zárubně/rámu_nahoře: 0.08 m; Ochrana proti kouři: no; Nouzový východ: no; Zárubeň/Rám_Typ: Dřevěný rám 92 mm; Zárubeň/Rám_Materiál: Dřevěný lepený eurohranol; Zárubeň/Rám_Povrch: Bílý lak; Křídlo_Materiál: Dřevěný lepený eurohranol; Křídlo_Povrch_Int.: Bílý lak; Křídlo_Povrch_Ext.: Bílý lak; Kování_Klika_Ext.: není; Kování_Zámek: není; Kování_Klika_Int.: Okenní klika; Specifikace: Dvojkřídlové okno otevíravé a sklápěcí, symetricky dělené s nadsvětlíkem; Height: 2 m; Length: 1.5 m; Kování_Závěsy: Celoobvodové kování s pětibodovým uzávěrem; Typ skla: Izolační trojsklo 4-18-4-18-4 Ug 0,5; Pset_BuildingElementProxyCommon - ThermalTransmittance: 0.8 W/K/m2
 | Půdorys 3.NP | EPS | Zateplovací systémy |  |  | EPS | 1652Zas0798443681 | m2 | Zaslepení | 1
O06 | Půdorys 3.NP |  |  | 0 | O06 |  | 1652Obj0798436200 | Kus | Okno - objekt+SmartPart | 1 | NEMSOK - Verze programu: 2.2; Plugin_Bezeichnung: MainObject; Plugin_Objektname: SmartPartCompressed; Verze: 3.0; Dolní_hrana: 0 m; Horní_hrana: 0 m; Jednotková_cena: 0; Uvažované procento prosklení: 100; Plocha_skla: 1.6864; Výška_vnějšího_parapetu: 0 m; Výška_vnitřního_parapetu: 0 m; Odstup_od_otvoru_dole: 0 m; Odstup_od_otvoru_nahoře: 0 m; Odstup_od_otvoru_vlevo: 0 m; Odstup_od_otvoru_vpravo: 0 m; Tloušťka_zárubně/rámu_dole: 0.08 m; Tloušťka_zárubně/rámu_vlevo: 0.08 m; Tloušťka_zárubně/rámu_vpravo: 0.08 m; Tloušťka_zárubně/rámu_nahoře: 0.08 m; Ochrana proti kouři: no; Nouzový východ: no; Zárubeň/Rám_Typ: Dřevěný rám 92 mm; Zárubeň/Rám_Materiál: Dřevěný lepený eurohranol; Zárubeň/Rám_Povrch: Bílý lak; Křídlo_Materiál: Dřevěný lepený eurohranol; Křídlo_Povrch_Int.: Bílý lak; Křídlo_Povrch_Ext.: Bílý lak; Kování_Klika_Ext.: není; Kování_Zámek: není; Kování_Klika_Int.: Okenní klika; Specifikace: Dvojkřídlové okno otevíravé a sklápěcí, symetricky dělené s nadsvětlíkem; Height: 1.8 m; Length: 1.5 m; Kování_Závěsy: Celoobvodové kování s pětibodovým uzávěrem; Typ skla: Izolační trojsklo 4-18-4-18-4 Ug 0,5; Pset_BuildingElementProxyCommon - ThermalTransmittance: 0.8 W/K/m2
 | Půdorys 3.NP | EPS | Zateplovací systémy |  |  | EPS | 1652Zas0798444339 | m2 | Zaslepení | 1
Parapet vnější | Půdorys 4.NP | PLECH | Klempířské práce | 0 | Parapet vnější | PLECH | 1752Obj0000010126 | m | Parapet - objekt+SmartPart | 1 | NEMSOK - Absolutní_výška: 0.03 m; Tloušťka: 0.1 m; Výška: 0.005 m; Objem: 0.0012505; Plocha: 0.2156; Poloha (vnitřní/venkovní): 1
Parapet vnější | Půdorys 4.NP | PLECH | Klempířské práce | 0 | Parapet vnější | PLECH | 1752Obj0000010131 | m | Parapet - objekt+SmartPart | 1 | NEMSOK - Absolutní_výška: 0.03 m; Tloušťka: 0.1 m; Výška: 0.005 m; Objem: 0.0012505; Plocha: 0.2156; Poloha (vnitřní/venkovní): 1
Parapet vnější | Půdorys 4.NP | PLECH | Klempířské práce | 0 | Parapet vnější | PLECH | 1752Obj0000010138 | m | Parapet - objekt+SmartPart | 1 | NEMSOK - Absolutní_výška: 0.03 m; Tloušťka: 0.1 m; Výška: 0.005 m; Objem: 0.0012505; Plocha: 0.2156; Poloha (vnitřní/venkovní): 1
Parapet vnější | Půdorys 4.NP | PLECH | Klempířské práce | 0 | Parapet vnější | PLECH | 1752Obj0000010330 | m | Parapet - objekt+SmartPart | 1 | NEMSOK - Absolutní_výška: 0.03 m; Tloušťka: 0.1 m; Výška: 0.005 m; Objem: 0.0012505; Plocha: 0.2156; Poloha (vnitřní/venkovní): 1
Parapet vnější | Půdorys 4.NP | PLECH | Klempířské práce | 0 | Parapet vnější | PLECH | 1752Obj0000010366 | m | Parapet - objekt+SmartPart | 1 | NEMSOK - Absolutní_výška: 0.03 m; Tloušťka: 0.1 m; Výška: 0.005 m; Objem: 0.0012505; Plocha: 0.2156; Poloha (vnitřní/venkovní): 1
Parapet vnější | Půdorys 4.NP | PLECH | Klempířské práce | 0 | Parapet vnější | PLECH | 1752Obj0000010370 | m | Parapet - objekt+SmartPart | 1 | NEMSOK - Absolutní_výška: 0.03 m; Tloušťka: 0.1 m; Výška: 0.005 m; Objem: 0.0012505; Plocha: 0.2156; Poloha (vnitřní/venkovní): 1
Parapet vnější | Půdorys 4.NP | PLECH | Klempířské práce | 0 | Parapet vnější | PLECH | 1752Obj0000010372 | m | Parapet - objekt+SmartPart | 1 | NEMSOK - Absolutní_výška: 0.03 m; Tloušťka: 0.1 m; Výška: 0.005 m; Objem: 0.0012505; Plocha: 0.2156; Poloha (vnitřní/venkovní): 1
Parapet vnější | Půdorys 4.NP | PLECH | Klempířské práce | 0 | Parapet vnější | PLECH | 1752Obj0000010374 | m | Parapet - objekt+SmartPart | 1 | NEMSOK - Absolutní_výška: 0.03 m; Tloušťka: 0.1 m; Výška: 0.005 m; Objem: 0.0012505; Plocha: 0.2156; Poloha (vnitřní/venkovní): 1
Parapet vnější | Půdorys 4.NP | PLECH | Klempířské práce | 0 | Parapet vnější | PLECH | 1752Obj0000010368 | m | Parapet - objekt+SmartPart | 1 | NEMSOK - Absolutní_výška: 0.03 m; Tloušťka: 0.1 m; Výška: 0.005 m; Objem: 0.0012505; Plocha: 0.2156; Poloha (vnitřní/venkovní): 1
Ocelový profil | Půdorys 4.NP | U 140 |  | 0 | Ocelový profil | U 140 | 1752Sma0000001512 | Kus | SmartPart | 1 | NEMSOK - Verze programu: 1.0; Plugin_Bezeichnung: MainObject; Plugin_Objektname: SmartPartCompressed; Verze: 1.0; Dolní_hrana: 0 m; Horní_hrana: 0 m
Parapet vnější | Půdorys 4.NP | PLECH | Klempířské práce | 0 | Parapet vnější | PLECH | 1752Obj0000010261 | m | Parapet - objekt+SmartPart | 1 | NEMSOK - Absolutní_výška: 0.03 m; Tloušťka: 0.1 m; Výška: 0.005 m; Objem: 0.0012505; Plocha: 0.2156; Poloha (vnitřní/venkovní): 1
Parapet vnější | Půdorys 4.NP | PLECH | Klempířské práce | 0 | Parapet vnější | PLECH | 1752Obj0000016532 | m | Parapet - objekt+SmartPart | 1 | NEMSOK - Absolutní_výška: 0.03 m; Tloušťka: 0.1 m; Výška: 0.005 m; Objem: 0.0012505; Plocha: 0.2156; Poloha (vnitřní/venkovní): 1
Parapet vnější | Půdorys 4.NP | PLECH | Klempířské práce | 0 | Parapet vnější | PLECH | 1752Obj0000016555 | m | Parapet - objekt+SmartPart | 1 | NEMSOK - Absolutní_výška: 0.03 m; Tloušťka: 0.1 m; Výška: 0.005 m; Objem: 0.0012505; Plocha: 0.2156; Poloha (vnitřní/venkovní): 1
Parapet vnější | Půdorys 4.NP | PLECH | Klempířské práce | 0 | Parapet vnější | PLECH | 1752Obj0798429939 | m | Parapet - objekt+SmartPart | 1 | NEMSOK - Absolutní_výška: 0.03 m; Tloušťka: 0.2 m; Výška: 0.005 m; Objem: 0.0019475; Plocha: 0.36; Poloha (vnitřní/venkovní): 1
 | Půdorys 4.NP | EPS | Zateplovací systémy |  |  | EPS | 1752Zas0798429943 | m2 | Zaslepení | 1
Parapet vnější | Půdorys 4.NP | PLECH | Klempířské práce | 0 | Parapet vnější | PLECH | 1752Obj0798429776 | m | Parapet - objekt+SmartPart | 1 | NEMSOK - Absolutní_výška: 0.03 m; Tloušťka: 0.2 m; Výška: 0.005 m; Objem: 0.0018945; Plocha: 0.3504; Poloha (vnitřní/venkovní): 1
 | Půdorys 4.NP | EPS | Zateplovací systémy |  |  | EPS | 1752Zas0798429809 | m2 | Zaslepení | 1
Parapet vnější | Půdorys 4.NP | PLECH | Klempířské práce | 0 | Parapet vnější | PLECH | 1752Obj0000017182 | m | Parapet - objekt+SmartPart | 1 | NEMSOK - Absolutní_výška: 0.03 m; Tloušťka: 0.1 m; Výška: 0.005 m; Objem: 0.001003; Plocha: 0.1736; Poloha (vnitřní/venkovní): 1
Parapet vnější | Půdorys 4.NP | PLECH | Klempířské práce | 0 | Parapet vnější | PLECH | 1752Obj0000017142 | m | Parapet - objekt+SmartPart | 1 | NEMSOK - Absolutní_výška: 0.03 m; Tloušťka: 0.1 m; Výška: 0.005 m; Objem: 0.001003; Plocha: 0.1736; Poloha (vnitřní/venkovní): 1
Parapet vnější | Půdorys 4.NP | PLECH | Klempířské práce | 0 | Parapet vnější | PLECH | 1752Obj0000017102 | m | Parapet - objekt+SmartPart | 1 | NEMSOK - Absolutní_výška: 0.03 m; Tloušťka: 0.1 m; Výška: 0.005 m; Objem: 0.001003; Plocha: 0.1736; Poloha (vnitřní/venkovní): 1
Parapet vnější | Půdorys 4.NP | PLECH | Klempířské práce | 0 | Parapet vnější | PLECH | 1752Obj0000017062 | m | Parapet - objekt+SmartPart | 1 | NEMSOK - Absolutní_výška: 0.03 m; Tloušťka: 0.1 m; Výška: 0.005 m; Objem: 0.001003; Plocha: 0.1736; Poloha (vnitřní/venkovní): 1
Parapet vnější | Půdorys 4.NP | PLECH | Klempířské práce | 0 | Parapet vnější | PLECH | 1752Obj0000017022 | m | Parapet - objekt+SmartPart | 1 | NEMSOK - Absolutní_výška: 0.03 m; Tloušťka: 0.1 m; Výška: 0.005 m; Objem: 0.0012505; Plocha: 0.2156; Poloha (vnitřní/venkovní): 1
Parapet vnější | Půdorys 4.NP | PLECH | Klempířské práce | 0 | Parapet vnější | PLECH | 1752Obj0000016982 | m | Parapet - objekt+SmartPart | 1 | NEMSOK - Absolutní_výška: 0.03 m; Tloušťka: 0.1 m; Výška: 0.005 m; Objem: 0.0012505; Plocha: 0.2156; Poloha (vnitřní/venkovní): 1
Parapet vnější | Půdorys 4.NP | PLECH | Klempířské práce | 0 | Parapet vnější | PLECH | 1752Obj0000016942 | m | Parapet - objekt+SmartPart | 1 | NEMSOK - Absolutní_výška: 0.03 m; Tloušťka: 0.1 m; Výška: 0.005 m; Objem: 0.0012505; Plocha: 0.2156; Poloha (vnitřní/venkovní): 1
Parapet vnější | Půdorys 4.NP | PLECH | Klempířské práce | 0 | Parapet vnější | PLECH | 1752Obj0000016902 | m | Parapet - objekt+SmartPart | 1 | NEMSOK - Absolutní_výška: 0.03 m; Tloušťka: 0.1 m; Výška: 0.005 m; Objem: 0.0012505; Plocha: 0.2156; Poloha (vnitřní/venkovní): 1
Parapet vnější | Půdorys 4.NP | PLECH | Klempířské práce | 0 | Parapet vnější | PLECH | 1752Obj0000016862 | m | Parapet - objekt+SmartPart | 1 | NEMSOK - Absolutní_výška: 0.03 m; Tloušťka: 0.1 m; Výška: 0.005 m; Objem: 0.0012505; Plocha: 0.2156; Poloha (vnitřní/venkovní): 1
Parapet vnější | Půdorys 4.NP | PLECH | Klempířské práce | 0 | Parapet vnější | PLECH | 1752Obj0000016750 | m | Parapet - objekt+SmartPart | 1 | NEMSOK - Absolutní_výška: 0.03 m; Tloušťka: 0.1 m; Výška: 0.005 m; Objem: 0.0012505; Plocha: 0.2156; Poloha (vnitřní/venkovní): 1
Parapet vnější | Půdorys 4.NP | PLECH | Klempířské práce | 0 | Parapet vnější | PLECH | 1752Obj0000016679 | m | Parapet - objekt+SmartPart | 1 | NEMSOK - Absolutní_výška: 0.03 m; Tloušťka: 0.1 m; Výška: 0.005 m; Objem: 0.001003; Plocha: 0.1736; Poloha (vnitřní/venkovní): 1
Parapet vnější | Půdorys 4.NP | PLECH | Klempířské práce | 0 | Parapet vnější | PLECH | 1752Obj0000016639 | m | Parapet - objekt+SmartPart | 1 | NEMSOK - Absolutní_výška: 0.03 m; Tloušťka: 0.1 m; Výška: 0.005 m; Objem: 0.001003; Plocha: 0.1736; Poloha (vnitřní/venkovní): 1
Parapet vnější | Půdorys 4.NP | PLECH | Klempířské práce | 0 | Parapet vnější | PLECH | 1752Obj0000016599 | m | Parapet - objekt+SmartPart | 1 | NEMSOK - Absolutní_výška: 0.03 m; Tloušťka: 0.1 m; Výška: 0.005 m; Objem: 0.001003; Plocha: 0.1736; Poloha (vnitřní/venkovní): 1
Parapet vnější | Půdorys 4.NP | PLECH | Klempířské práce | 0 | Parapet vnější | PLECH | 1752Obj0000016577 | m | Parapet - objekt+SmartPart | 1 | NEMSOK - Absolutní_výška: 0.03 m; Tloušťka: 0.1 m; Výška: 0.005 m; Objem: 0.001003; Plocha: 0.1736; Poloha (vnitřní/venkovní): 1
Ocelový profil | Půdorys 5.NP | U 140 |  | 0 | Ocelový profil | U 140 | 1852Sma0000006454 | Kus | SmartPart | 1 | NEMSOK - Verze programu: 1.0; Plugin_Bezeichnung: MainObject; Plugin_Objektname: SmartPartCompressed; Verze: 1.0; Dolní_hrana: 0 m; Horní_hrana: 0 m
Ocelový profil | Půdorys 5.NP | U 140 |  | 0 | Ocelový profil | U 140 | 1852Sma0000001486 | Kus | SmartPart | 1 | NEMSOK - Verze programu: 1.0; Plugin_Bezeichnung: MainObject; Plugin_Objektname: SmartPartCompressed; Verze: 1.0; Dolní_hrana: 0 m; Horní_hrana: 0 m
Ocelový profil | Půdorys 5.NP | U 140 |  | 0 | Ocelový profil | U 140 | 1852Sma0000001485 | Kus | SmartPart | 1 | NEMSOK - Verze programu: 1.0; Plugin_Bezeichnung: MainObject; Plugin_Objektname: SmartPartCompressed; Verze: 1.0; Dolní_hrana: 0 m; Horní_hrana: 0 m
D101 | Půdorys 5.NP |  |  | 0 | D101 |  | 1852Obj0798428189 | Kus | Objekt | 1 | NEMSOK - Verze programu: 2.2; Plugin_Bezeichnung: MainObject; Plugin_Objektname: SmartPartCompressed; Verze: 4.0; Jednotková_cena: 0; Uvažované procento prosklení: 100; Plocha_skla: 0; Výška_vnějšího_parapetu: 0 m; Výška_vnitřního_parapetu: 0 m; Odstup_od_otvoru_dole: 0 m; Odstup_od_otvoru_nahoře: 0 m; Odstup_od_otvoru_vlevo: 0 m; Odstup_od_otvoru_vpravo: 0 m; Tloušťka_zárubně/rámu_dole: 0 m; Tloušťka_zárubně/rámu_vlevo: 0.02 m; Tloušťka_zárubně/rámu_vpravo: 0.02 m; Tloušťka_zárubně/rámu_nahoře: 0.02 m; Ochrana proti kouři: no; Nouzový východ: no; Zárubeň/Rám_Materiál: Ocelová; Zárubeň/Rám_Povrch: EH; Samozavírací: no; Bezbariérový přístup: no; Dveře_Světlá-šířka: 0 m; Dveře_Světlá-výška: 0 m; Specifikace: Interiérové dveře jednokřídlé plné; Koordinátor zavírání dveří: yes; Name: 1970; Profile: 900; Grade: 2135; Finish: 100; Pset_BuildingElementProxyCommon - ThermalTransmittance: 0 W/K/m2; IsExternal: no
OCELOVÁ KCE | Půdorys 5.NP |  |  | 0 | OCELOVÁ KCE | OCELOVÁ KCE | 1852Obj0798428440 | Kus | ŽEBŘÍK NA STŘECHU | 1
Parapet vnější | Půdorys 5.NP | PLECH | Klempířské práce | 0 | Parapet vnější | PLECH | 1852Obj0798433166 | m | Parapet - objekt+SmartPart | 1 | NEMSOK - Absolutní_výška: 0.03 m; Tloušťka: 0.1 m; Výška: 0.005 m; Objem: 0.0007555; Plocha: 0.1316; Poloha (vnitřní/venkovní): 1
Parapet vnější | Půdorys 5.NP | PLECH | Klempířské práce | 0 | Parapet vnější | PLECH | 1852Obj0798432421 | m | Parapet - objekt+SmartPart | 1 | NEMSOK - Absolutní_výška: 0.03 m; Tloušťka: 0.1 m; Výška: 0.005 m; Objem: 0.0007555; Plocha: 0.1316; Poloha (vnitřní/venkovní): 1
Parapet vnější | Půdorys 5.NP | PLECH | Klempířské práce | 0 | Parapet vnější | PLECH | 1852Obj0798432462 | m | Parapet - objekt+SmartPart | 1 | NEMSOK - Absolutní_výška: 0.03 m; Tloušťka: 0.2 m; Výška: 0.005 m; Objem: 0.0012055; Plocha: 0.2256; Poloha (vnitřní/venkovní): 1
ŽEBŘÍK PŘES ATIKU | Půdorys 5.NP |  |  | 0 | ŽEBŘÍK PŘES ATIKU |  | 1864Obj0000021600 | Kus | I.Z5.1 | 1 | NEMSOK - Kód prvku: ZV00.06.0001
Ocelový profil | Půdorys 6.NP | I 260 |  | 0 | Ocelový profil | I 260 | 1954Sma0000000376 | Kus | SmartPart | 1 | NEMSOK - Verze programu: 1.0; Plugin_Bezeichnung: MainObject; Plugin_Objektname: SmartPartCompressed; Verze: 1.0; Dolní_hrana: 0 m; Horní_hrana: 0 m
Ocelový profil | Půdorys 6.NP | I 260 |  | 0 | Ocelový profil | I 260 | 1954Sma0000000377 | Kus | SmartPart | 1 | NEMSOK - Verze programu: 1.0; Plugin_Bezeichnung: MainObject; Plugin_Objektname: SmartPartCompressed; Verze: 1.0; Dolní_hrana: 0 m; Horní_hrana: 0 m
Ocelový profil | Půdorys 6.NP | I 260 |  | 0 | Ocelový profil | I 260 | 1954Sma0000000378 | Kus | SmartPart | 1 | NEMSOK - Verze programu: 1.0; Plugin_Bezeichnung: MainObject; Plugin_Objektname: SmartPartCompressed; Verze: 1.0; Dolní_hrana: 0 m; Horní_hrana: 0 m
Ocelový profil | Půdorys 6.NP | I 260 |  | 0 | Ocelový profil | I 260 | 1954Sma0000000379 | Kus | SmartPart | 1 | NEMSOK - Verze programu: 1.0; Plugin_Bezeichnung: MainObject; Plugin_Objektname: SmartPartCompressed; Verze: 1.0; Dolní_hrana: 0 m; Horní_hrana: 0 m
Ocelový profil | Půdorys 6.NP | I 260 |  | 0 | Ocelový profil | I 260 | 1954Sma0000000382 | Kus | SmartPart | 1 | NEMSOK - Verze programu: 1.0; Plugin_Bezeichnung: MainObject; Plugin_Objektname: SmartPartCompressed; Verze: 1.0; Dolní_hrana: 0 m; Horní_hrana: 0 m
Ocelový profil | Půdorys 6.NP | I 260 |  | 0 | Ocelový profil | I 260 | 1954Sma0000000380 | Kus | SmartPart | 1 | NEMSOK - Verze programu: 1.0; Plugin_Bezeichnung: MainObject; Plugin_Objektname: SmartPartCompressed; Verze: 1.0; Dolní_hrana: 0 m; Horní_hrana: 0 m
Ocelový profil | Půdorys 6.NP | I 260 |  | 0 | Ocelový profil | I 260 | 1954Sma0000000381 | Kus | SmartPart | 1 | NEMSOK - Verze programu: 1.0; Plugin_Bezeichnung: MainObject; Plugin_Objektname: SmartPartCompressed; Verze: 1.0; Dolní_hrana: 0 m; Horní_hrana: 0 m
Ocelový profil | Půdorys 6.NP | I 180 |  | 0 | Ocelový profil | I 180 | 1954Sma0000000394 | Kus | SmartPart | 1 | NEMSOK - Verze programu: 1.0; Plugin_Bezeichnung: MainObject; Plugin_Objektname: SmartPartCompressed; Verze: 1.0; Dolní_hrana: 0 m; Horní_hrana: 0 m
Ocelový profil | Půdorys 6.NP | I 180 |  | 0 | Ocelový profil | I 180 | 1954Sma0000000399 | Kus | SmartPart | 1 | NEMSOK - Verze programu: 1.0; Plugin_Bezeichnung: MainObject; Plugin_Objektname: SmartPartCompressed; Verze: 1.0; Dolní_hrana: 0 m; Horní_hrana: 0 m
Ocelový profil | Půdorys 6.NP | I 180 |  | 0 | Ocelový profil | I 180 | 1954Sma0000000400 | Kus | SmartPart | 1 | NEMSOK - Verze programu: 1.0; Plugin_Bezeichnung: MainObject; Plugin_Objektname: SmartPartCompressed; Verze: 1.0; Dolní_hrana: 0 m; Horní_hrana: 0 m
Ocelový profil | Půdorys 6.NP | I 180 |  | 0 | Ocelový profil | I 180 | 1954Sma0000000401 | Kus | SmartPart | 1 | NEMSOK - Verze programu: 1.0; Plugin_Bezeichnung: MainObject; Plugin_Objektname: SmartPartCompressed; Verze: 1.0; Dolní_hrana: 0 m; Horní_hrana: 0 m
Ocelový profil | Půdorys 6.NP | I 180 |  | 0 | Ocelový profil | I 180 | 1954Sma0000000402 | Kus | SmartPart | 1 | NEMSOK - Verze programu: 1.0; Plugin_Bezeichnung: MainObject; Plugin_Objektname: SmartPartCompressed; Verze: 1.0; Dolní_hrana: 0 m; Horní_hrana: 0 m
Ocelový profil | Půdorys 6.NP | I 180 |  | 0 | Ocelový profil | I 180 | 1954Sma0000000403 | Kus | SmartPart | 1 | NEMSOK - Verze programu: 1.0; Plugin_Bezeichnung: MainObject; Plugin_Objektname: SmartPartCompressed; Verze: 1.0; Dolní_hrana: 0 m; Horní_hrana: 0 m
6 x  | Půdorys 6.NP
6 x  | Půdorys střechy
VÝLEZ NA STŘECHU | Půdorys střechy |  |  | 0 | VÝLEZ NA STŘECHU |  | 2481Sma0000000964 | Kus | I.VS2 | 1 | NEMSOK - Kód prvku: OV00.08.0001; Verze programu: 2.2; Plugin_Bezeichnung: MainObject; Plugin_Objektname: SmartPartCompressed; Verze: 2.1; Výška_podstavy_světlíku: 0.95 m; Výška_kopule_světlíku: 0.06 m

# IfcColumn (605)
PredefinedType: COLUMN
NEMSOK - 2D interakce: yes
Name | In | Material = Materiál | Práce | Stupeň vyztužení | Číslo parkovacího místa | LOD | Allright_Stavebni_dil_ID | Jednotka | Název_objektu | Status | LoadBearing | Width (m) | Depth (m) | CrossSectionArea (m2) | GrossVolume (m3) | NetVolume (m3) | Length (m) | OuterSurfaceArea (m2)
 | Půdorys 1.PP | ZELEZOBETONOVÁ KCE | Betonářské práce | 0 | 0 | @452@ | 1302Slo0000000097 | m3 | Sloup | EXISTING | yes | 0.4 | 0.4 | 0.16 | 0.491 | 0.491 | 3.07 | 4.912
 | Půdorys 1.PP | ZELEZOBETONOVÁ KCE | Betonářské práce | 0 | 0 | @452@ | 1302Slo0000000079 | m3 | Sloup | EXISTING | yes | 0.4 | 0.4 | 0.16 | 0.491 | 0.491 | 3.07 | 4.912
 | Půdorys 1.PP | ZELEZOBETONOVÁ KCE | Betonářské práce | 0 | 0 | @452@ | 1302Slo0000000041 | m3 | Sloup | EXISTING | yes | 0.4 | 0.4 | 0.16 | 0.491 | 0.491 | 3.07 | 4.912
 | Půdorys 1.PP | ZELEZOBETONOVÁ KCE | Betonářské práce | 0 | 0 | @452@ | 1302Slo0000000039 | m3 | Sloup | EXISTING | yes | 0.4 | 0.4 | 0.16 | 0.491 | 0.491 | 3.07 | 4.912
 | Půdorys 1.PP | ZELEZOBETONOVÁ KCE | Betonářské práce | 0 | 0 | @452@ | 1302Slo0000000109 | m3 | Sloup | EXISTING | yes | 0.4 | 0.4 | 0.16 | 0.491 | 0.491 | 3.07 | 4.912
 | Půdorys 1.PP | ZELEZOBETONOVÁ KCE | Betonářské práce | 0 | 0 | @452@ | 1302Slo0000000043 | m3 | Sloup | EXISTING | yes | 0.4 | 0.4 | 0.16 | 0.491 | 0.491 | 3.07 | 4.912
 | Půdorys 1.PP | ZELEZOBETONOVÁ KCE | Betonářské práce | 0 | 0 | @452@ | 1302Slo0000000005 | m3 | Sloup | EXISTING | yes | 0.4 | 0.4 | 0.16 | 0.491 | 0.491 | 3.07 | 4.912
 | Půdorys 1.PP | ZELEZOBETONOVÁ KCE | Betonářské práce | 0 | 0 | @452@ | 1302Slo0000000095 | m3 | Sloup | EXISTING | yes | 0.4 | 0.4 | 0.16 | 0.491 | 0.491 | 3.07 | 4.912
 | Půdorys 1.PP | ZELEZOBETONOVÁ KCE | Betonářské práce | 0 | 0 | @452@ | 1302Slo0000000071 | m3 | Sloup | EXISTING | yes | 0.4 | 0.4 | 0.16 | 0.491 | 0.491 | 3.07 | 4.912
 | Půdorys 1.PP | ZELEZOBETONOVÁ KCE | Betonářské práce | 0 | 0 | @452@ | 1302Slo0000000021 | m3 | Sloup | EXISTING | yes | 0.4 | 0.4 | 0.16 | 0.491 | 0.491 | 3.07 | 4.912
 | Půdorys 1.PP | ZELEZOBETONOVÁ KCE | Betonářské práce | 0 | 0 | @452@ | 1302Slo0000000019 | m3 | Sloup | EXISTING | yes | 0.4 | 0.4 | 0.16 | 0.491 | 0.491 | 3.07 | 4.912
 | Půdorys 1.PP | ZELEZOBETONOVÁ KCE | Betonářské práce | 0 | 0 | @452@ | 1302Slo0000000017 | m3 | Sloup | EXISTING | yes | 0.4 | 0.4 | 0.16 | 0.491 | 0.491 | 3.07 | 4.912
 | Půdorys 1.PP | ZELEZOBETONOVÁ KCE | Betonářské práce | 0 | 0 | @452@ | 1302Slo0000000015 | m3 | Sloup | EXISTING | yes | 0.4 | 0.4 | 0.16 | 0.491 | 0.491 | 3.07 | 4.912
 | Půdorys 1.PP | ZELEZOBETONOVÁ KCE | Betonářské práce | 0 | 0 | @452@ | 1302Slo0000000013 | m3 | Sloup | EXISTING | yes | 0.4 | 0.4 | 0.16 | 0.491 | 0.491 | 3.07 | 4.912
 | Půdorys 1.PP | ZELEZOBETONOVÁ KCE | Betonářské práce | 0 | 0 | @452@ | 1302Slo0000000011 | m3 | Sloup | EXISTING | yes | 0.4 | 0.4 | 0.16 | 0.491 | 0.491 | 3.07 | 4.912
 | Půdorys 1.PP | ZELEZOBETONOVÁ KCE | Betonářské práce | 0 | 0 | @452@ | 1302Slo0000000007 | m3 | Sloup | EXISTING | yes | 0.4 | 0.4 | 0.16 | 0.491 | 0.491 | 3.07 | 4.912
 | Půdorys 1.PP | ZELEZOBETONOVÁ KCE | Betonářské práce | 0 | 0 | @452@ | 1302Slo0000000093 | m3 | Sloup | EXISTING | yes | 0.4 | 0.4 | 0.16 | 0.491 | 0.491 | 3.07 | 4.912
 | Půdorys 1.PP | ZELEZOBETONOVÁ KCE | Betonářské práce | 0 | 0 | @452@ | 1302Slo0000000049 | m3 | Sloup | EXISTING | yes | 0.4 | 0.4 | 0.16 | 0.491 | 0.491 | 3.07 | 4.912
 | Půdorys 1.PP | ZELEZOBETONOVÁ KCE | Betonářské práce | 0 | 0 | @452@ | 1302Slo0000000051 | m3 | Sloup | EXISTING | yes | 0.4 | 0.4 | 0.16 | 0.491 | 0.491 | 3.07 | 4.912
 | Půdorys 1.PP | ZELEZOBETONOVÁ KCE | Betonářské práce | 0 | 0 | @452@ | 1302Slo0000000053 | m3 | Sloup | EXISTING | yes | 0.4 | 0.4 | 0.16 | 0.491 | 0.491 | 3.07 | 4.912
 | Půdorys 1.PP | ZELEZOBETONOVÁ KCE | Betonářské práce | 0 | 0 | @452@ | 1302Slo0000000055 | m3 | Sloup | EXISTING | yes | 0.4 | 0.4 | 0.16 | 0.491 | 0.491 | 3.07 | 4.912
 | Půdorys 1.PP | ZELEZOBETONOVÁ KCE | Betonářské práce | 0 | 0 | @452@ | 1302Slo0000000057 | m3 | Sloup | EXISTING | yes | 0.4 | 0.4 | 0.16 | 0.491 | 0.491 | 3.07 | 4.912
 | Půdorys 1.PP | ZELEZOBETONOVÁ KCE | Betonářské práce | 0 | 0 | @452@ | 1302Slo0000000059 | m3 | Sloup | EXISTING | yes | 0.4 | 0.4 | 0.16 | 0.491 | 0.491 | 3.07 | 4.912
 | Půdorys 1.PP | ZELEZOBETONOVÁ KCE | Betonářské práce | 0 | 0 | @452@ | 1302Slo0000000061 | m3 | Sloup | EXISTING | yes | 0.4 | 0.4 | 0.16 | 0.491 | 0.491 | 3.07 | 4.912
 | Půdorys 1.PP | ZELEZOBETONOVÁ KCE | Betonářské práce | 0 | 0 | @452@ | 1302Slo0000000063 | m3 | Sloup | EXISTING | yes | 0.4 | 0.4 | 0.16 | 0.491 | 0.491 | 3.07 | 4.912
 | Půdorys 1.PP | ZELEZOBETONOVÁ KCE | Betonářské práce | 0 | 0 | @452@ | 1302Slo0000000065 | m3 | Sloup | EXISTING | yes | 0.4 | 0.4 | 0.16 | 0.491 | 0.491 | 3.07 | 4.912
 | Půdorys 1.PP | ZELEZOBETONOVÁ KCE | Betonářské práce | 0 | 0 | @452@ | 1302Slo0000000067 | m3 | Sloup | EXISTING | yes | 0.4 | 0.4 | 0.16 | 0.491 | 0.491 | 3.07 | 4.912
 | Půdorys 1.PP | ZELEZOBETONOVÁ KCE | Betonářské práce | 0 | 0 | @452@ | 1302Slo0000000101 | m3 | Sloup | EXISTING | yes | 0.4 | 0.4 | 0.16 | 0.491 | 0.491 | 3.07 | 4.912
 | Půdorys 1.PP | ZELEZOBETONOVÁ KCE | Betonářské práce | 0 | 0 | @452@ | 1302Slo0000000107 | m3 | Sloup | EXISTING | yes | 0.4 | 0.4 | 0.16 | 0.491 | 0.491 | 3.07 | 4.912
 | Půdorys 1.PP | ZELEZOBETONOVÁ KCE | Betonářské práce | 0 | 0 | @452@ | 1302Slo0000000127 | m3 | Sloup | EXISTING | yes | 0.4 | 0.4 | 0.16 | 0.491 | 0.491 | 3.07 | 4.912
 | Půdorys 1.PP | ZELEZOBETONOVÁ KCE | Betonářské práce | 0 | 0 | @452@ | 1302Slo0000000111 | m3 | Sloup | EXISTING | yes | 0.4 | 0.4 | 0.16 | 0.491 | 0.491 | 3.07 | 4.912
 | Půdorys 1.PP | ZELEZOBETONOVÁ KCE | Betonářské práce | 0 | 0 | @452@ | 1302Slo0000000089 | m3 | Sloup | EXISTING | yes | 0.4 | 0.4 | 0.16 | 0.491 | 0.491 | 3.07 | 4.912
 | Půdorys 1.PP | ZELEZOBETONOVÁ KCE | Betonářské práce | 0 | 0 | @452@ | 1302Slo0000000085 | m3 | Sloup | EXISTING | yes | 1 | 0.6 | 0.6 | 1.842 | 1.842 | 3.07 | 9.824
 | Půdorys 1.PP | ZELEZOBETONOVÁ KCE | Betonářské práce | 0 | 0 | @452@ | 1302Slo0000000025 | m3 | Sloup | EXISTING | yes | 0.4 | 0.4 | 0.16 | 0.491 | 0.491 | 3.07 | 4.912
 | Půdorys 1.PP | ZELEZOBETONOVÁ KCE | Betonářské práce | 0 | 0 | @452@ | 1302Slo0000000027 | m3 | Sloup | EXISTING | yes | 0.4 | 0.4 | 0.16 | 0.491 | 0.491 | 3.07 | 4.912
 | Půdorys 1.PP | ZELEZOBETONOVÁ KCE | Betonářské práce | 0 | 0 | @452@ | 1302Slo0000000031 | m3 | Sloup | EXISTING | yes | 0.4 | 0.4 | 0.16 | 0.491 | 0.491 | 3.07 | 4.912
 | Půdorys 1.PP | ZELEZOBETONOVÁ KCE | Betonářské práce | 0 | 0 | @452@ | 1302Slo0000000033 | m3 | Sloup | EXISTING | yes | 0.4 | 0.4 | 0.16 | 0.491 | 0.491 | 3.07 | 4.912
 | Půdorys 1.PP | ZELEZOBETONOVÁ KCE | Betonářské práce | 0 | 0 | @452@ | 1302Slo0000000029 | m3 | Sloup | EXISTING | yes | 0.4 | 0.4 | 0.16 | 0.491 | 0.491 | 3.07 | 4.912
 | Půdorys 1.PP | ZELEZOBETONOVÁ KCE | Betonářské práce | 0 | 0 | @452@ | 1302Slo0000000087 | m3 | Sloup | EXISTING | yes | 0.6 | 0.6 | 0.36 | 1.105 | 1.105 | 3.07 | 7.368
 | Půdorys 1.PP | ZELEZOBETONOVÁ KCE | Betonářské práce | 0 | 0 | @452@ | 1302Slo0000000105 | m3 | Sloup | EXISTING | yes | 0.4 | 0.4 | 0.16 | 0.491 | 0.491 | 3.07 | 4.912
 | Půdorys 1.PP | ZELEZOBETONOVÁ KCE | Betonářské práce | 0 | 0 | @452@ | 1302Slo0000000099 | m3 | Sloup | EXISTING | yes | 0.4 | 0.4 | 0.16 | 0.491 | 0.491 | 3.07 | 4.912
 | Půdorys 1.PP | ZELEZOBETONOVÁ KCE | Betonářské práce | 0 | 0 | @452@ | 1302Slo0000000081 | m3 | Sloup | EXISTING | yes | 0.4 | 0.4 | 0.16 | 0.491 | 0.491 | 3.07 | 4.912
 | Půdorys 1.PP | ZELEZOBETONOVÁ KCE | Betonářské práce | 0 | 0 | @452@ | 1302Slo0000000103 | m3 | Sloup | EXISTING | yes | 0.4 | 0.4 | 0.16 | 0.491 | 0.491 | 3.07 | 4.912
 | Půdorys 1.PP | ZELEZOBETONOVÁ KCE | Betonářské práce | 0 | 0 | @452@ | 1302Slo0000000045 | m3 | Sloup | EXISTING | yes | 0.4 | 0.4 | 0.16 | 0.491 | 0.491 | 3.07 | 4.912
 | Půdorys 1.PP | ZELEZOBETONOVÁ KCE | Betonářské práce | 0 | 0 | @452@ | 1302Slo0000000035 | m3 | Sloup | EXISTING | yes | 0.4 | 0.4 | 0.16 | 0.491 | 0.491 | 3.07 | 4.912
 | Půdorys 1.PP | ZELEZOBETONOVÁ KCE | Betonářské práce | 0 | 0 | @452@ | 1302Slo0000000123 | m3 | Sloup | EXISTING | yes | 0.4 | 0.4 | 0.16 | 0.491 | 0.491 | 3.07 | 4.912
 | Půdorys 1.PP | ZELEZOBETONOVÁ KCE | Betonářské práce | 0 | 0 | @452@ | 1302Slo0000000119 | m3 | Sloup | EXISTING | yes | 0.4 | 0.4 | 0.16 | 0.491 | 0.491 | 3.07 | 4.912
 | Půdorys 1.PP | ZELEZOBETONOVÁ KCE | Betonářské práce | 0 | 0 | @452@ | 1302Slo0000000121 | m3 | Sloup | EXISTING | yes | 0.4 | 0.4 | 0.16 | 0.491 | 0.491 | 3.07 | 4.912
 | Půdorys 1.PP | ZELEZOBETONOVÁ KCE | Betonářské práce | 0 | 0 | @452@ | 1302Slo0000000125 | m3 | Sloup | EXISTING | yes | 0.4 | 0.4 | 0.16 | 0.491 | 0.491 | 3.07 | 4.912
 | Půdorys 1.PP | ZELEZOBETONOVÁ KCE | Betonářské práce | 0 | 0 | @452@ | 1302Slo0000000113 | m3 | Sloup | EXISTING | yes | 0.4 | 0.4 | 0.16 | 0.491 | 0.491 | 3.07 | 4.912
 | Půdorys 1.PP | ZELEZOBETONOVÁ KCE | Betonářské práce | 0 | 0 | @452@ | 1302Slo0000000115 | m3 | Sloup | EXISTING | yes | 0.4 | 0.4 | 0.16 | 0.491 | 0.491 | 3.07 | 4.912
 | Půdorys 1.PP | ZELEZOBETONOVÁ KCE | Betonářské práce | 0 | 0 | @452@ | 1302Slo0000000117 | m3 | Sloup | EXISTING | yes | 0.4 | 0.4 | 0.16 | 0.491 | 0.491 | 3.07 | 4.912
 | Půdorys 1.PP | ZELEZOBETONOVÁ KCE | Betonářské práce | 0 | 0 | @452@ | 1302Slo0798450188 | m3 | Sloup | EXISTING | yes | 1 | 0.6 | 0.6 | 1.842 | 1.842 | 3.07 | 9.824
 | Půdorys 1.PP | ZELEZOBETONOVÁ KCE | Betonářské práce | 0 | 0 | @452@ | 1302Slo0000000091 | m3 | Sloup | EXISTING | yes | 0.4 | 0.4 | 0.16 | 0.491 | 0.491 | 3.07 | 4.912
 | Půdorys 1.NP | ZELEZOBETONOVÁ KCE | Betonářské práce | 0 | 0 | @452@ | 1402Slo0000000264 | m3 | Sloup | EXISTING | yes | 0.4 | 0.4 | 0.16 | 0.536 | 0.536 | 3.35 | 5.36
 | Půdorys 1.NP | ZELEZOBETONOVÁ KCE | Betonářské práce | 0 | 0 | @452@ | 1402Slo0000000261 | m3 | Sloup | EXISTING | yes | 0.4 | 0.4 | 0.16 | 0.536 | 0.536 | 3.35 | 5.36
 | Půdorys 1.NP | ZELEZOBETONOVÁ KCE | Betonářské práce | 0 | 0 | @452@ | 1402Slo0000000263 | m3 | Sloup | EXISTING | yes | 0.4 | 0.4 | 0.16 | 0.536 | 0.536 | 3.35 | 5.36
 | Půdorys 1.NP | ZELEZOBETONOVÁ KCE | Betonářské práce | 0 | 0 | @452@ | 1402Slo0000000012 | m3 | Sloup | EXISTING | yes | 0.4 | 0.4 | 0.16 | 0.536 | 0.536 | 3.35 | 5.36
 | Půdorys 1.NP | ZELEZOBETONOVÁ KCE | Betonářské práce | 0 | 0 | @452@ | 1402Slo0000000057 | m3 | Sloup | EXISTING | yes | 0.4 | 0.4 | 0.16 | 0.536 | 0.536 | 3.35 | 5.36
 | Půdorys 1.NP | ZELEZOBETONOVÁ KCE | Betonářské práce | 0 | 0 | @452@ | 1402Slo0000000266 | m3 | Sloup | EXISTING | yes | 0.4 | 0.4 | 0.16 | 0.536 | 0.536 | 3.35 | 5.36
 | Půdorys 1.NP | ZELEZOBETONOVÁ KCE | Betonářské práce | 0 | 0 | @452@ | 1402Slo0000000268 | m3 | Sloup | EXISTING | yes | 0.4 | 0.4 | 0.16 | 0.536 | 0.536 | 3.35 | 5.36
 | Půdorys 1.NP | ZELEZOBETONOVÁ KCE | Betonářské práce | 0 | 0 | @452@ | 1402Slo0000000265 | m3 | Sloup | EXISTING | yes | 0.4 | 0.4 | 0.16 | 0.536 | 0.536 | 3.35 | 5.36
 | Půdorys 1.NP | ZELEZOBETONOVÁ KCE | Betonářské práce | 0 | 0 | @452@ | 1402Slo0000000270 | m3 | Sloup | EXISTING | yes | 0.4 | 0.4 | 0.16 | 0.536 | 0.536 | 3.35 | 5.36
 | Půdorys 1.NP | ZELEZOBETONOVÁ KCE | Betonářské práce | 0 | 0 | @452@ | 1402Slo0000000056 | m3 | Sloup | EXISTING | yes | 0.4 | 0.4 | 0.16 | 0.539 | 0.539 | 3.37 | 5.392
 | Půdorys 1.NP | ZELEZOBETONOVÁ KCE | Betonářské práce | 0 | 0 | @452@ | 1402Slo0000000051 | m3 | Sloup | EXISTING | yes | 0.4 | 0.4 | 0.16 | 0.536 | 0.536 | 3.35 | 5.36
 | Půdorys 1.NP | ZELEZOBETONOVÁ KCE | Betonářské práce | 0 | 0 | @452@ | 1402Slo0798453496 | m3 | Sloup | EXISTING | yes | 0.4 | 0.4 | 0.16 | 0.536 | 0.536 | 3.35 | 5.36
 | Půdorys 1.NP | ZELEZOBETONOVÁ KCE | Betonářské práce | 0 | 0 | @452@ | 1402Slo0000000006 | m3 | Sloup | EXISTING | yes | 0.4 | 0.4 | 0.16 | 0.536 | 0.536 | 3.35 | 5.36
 | Půdorys 1.NP | ZELEZOBETONOVÁ KCE | Betonářské práce | 0 | 0 | @452@ | 1402Slo0000000008 | m3 | Sloup | EXISTING | yes | 0.4 | 0.4 | 0.16 | 0.536 | 0.536 | 3.35 | 5.36
 | Půdorys 1.NP | ZELEZOBETONOVÁ KCE | Betonářské práce | 0 | 0 | @452@ | 1402Slo0000000010 | m3 | Sloup | EXISTING | yes | 0.4 | 0.4 | 0.16 | 0.536 | 0.536 | 3.35 | 5.36
 | Půdorys 1.NP | ZELEZOBETONOVÁ KCE | Betonářské práce | 0 | 0 | @452@ | 1402Slo0000000048 | m3 | Sloup | EXISTING | yes | 0.4 | 0.4 | 0.16 | 0.536 | 0.536 | 3.35 | 5.36
 | Půdorys 1.NP | ZELEZOBETONOVÁ KCE | Betonářské práce | 0 | 0 | @452@ | 1402Slo0000000047 | m3 | Sloup | EXISTING | yes | 0.4 | 0.4 | 0.16 | 0.536 | 0.536 | 3.35 | 5.36
 | Půdorys 1.NP | ZELEZOBETONOVÁ KCE | Betonářské práce | 0 | 0 | @452@ | 1402Slo0000000260 | m3 | Sloup | EXISTING | yes | 0.4 | 0.4 | 0.16 | 0.536 | 0.536 | 3.35 | 5.36
 | Půdorys 1.NP | ZELEZOBETONOVÁ KCE | Betonářské práce | 0 | 0 | @452@ | 1402Slo0000000054 | m3 | Sloup | EXISTING | yes | 0.4 | 0.4 | 0.16 | 0.536 | 0.536 | 3.35 | 5.36
 | Půdorys 1.NP | ZELEZOBETONOVÁ KCE | Betonářské práce | 0 | 0 | @452@ | 1402Slo0000000053 | m3 | Sloup | EXISTING | yes | 0.4 | 0.4 | 0.16 | 0.536 | 0.536 | 3.35 | 5.36
 | Půdorys 1.NP | ZELEZOBETONOVÁ KCE | Betonářské práce | 0 | 0 | @452@ | 1402Slo0000000052 | m3 | Sloup | EXISTING | yes | 0.4 | 0.4 | 0.16 | 0.536 | 0.536 | 3.35 | 5.36
 | Půdorys 1.NP | ZELEZOBETONOVÁ KCE | Betonářské práce | 0 | 0 | @452@ | 1402Slo0798453494 | m3 | Sloup | EXISTING | yes | 0.4 | 0.4 | 0.16 | 0.536 | 0.536 | 3.35 | 5.36
 | Půdorys 1.NP | ZELEZOBETONOVÁ KCE | Betonářské práce | 0 | 0 | @452@ | 1402Slo0000000016 | m3 | Sloup | EXISTING | yes | 0.4 | 0.4 | 0.16 | 0.536 | 0.536 | 3.35 | 5.36
 | Půdorys 1.NP | ZELEZOBETONOVÁ KCE | Betonářské práce | 0 | 0 | @452@ | 1402Slo0000000225 | m3 | Sloup | EXISTING | yes | 0.4 | 0.4 | 0.16 | 0.536 | 0.536 | 3.35 | 5.36
 | Půdorys 1.NP | ZELEZOBETONOVÁ KCE | Betonářské práce | 0 | 0 | @452@ | 1402Slo0000000231 | m3 | Sloup | EXISTING | yes | 0.4 | 0.4 | 0.16 | 0.536 | 0.536 | 3.35 | 5.36
 | Půdorys 1.NP | ZELEZOBETONOVÁ KCE | Betonářské práce | 0 | 0 | @452@ | 1402Slo0000000018 | m3 | Sloup | EXISTING | yes | 0.4 | 0.4 | 0.16 | 0.536 | 0.536 | 3.35 | 5.36
 | Půdorys 1.NP | ZELEZOBETONOVÁ KCE | Betonářské práce | 0 | 0 | @452@ | 1402Slo0000000226 | m3 | Sloup | EXISTING | yes | 0.4 | 0.4 | 0.16 | 0.536 | 0.536 | 3.35 | 5.36
 | Půdorys 1.NP | ZELEZOBETONOVÁ KCE | Betonářské práce | 0 | 0 | @452@ | 1402Slo0000000227 | m3 | Sloup | EXISTING | yes | 0.4 | 0.4 | 0.16 | 0.536 | 0.536 | 3.35 | 5.36
 | Půdorys 1.NP | ZELEZOBETONOVÁ KCE | Betonářské práce | 0 | 0 | @452@ | 1402Slo0000000258 | m3 | Sloup | EXISTING | yes | 0.4 | 0.4 | 0.16 | 0.536 | 0.536 | 3.35 | 5.36
 | Půdorys 1.NP | ZELEZOBETONOVÁ KCE | Betonářské práce | 0 | 0 | @452@ | 1402Slo0000000257 | m3 | Sloup | EXISTING | yes | 0.4 | 0.4 | 0.16 | 0.536 | 0.536 | 3.35 | 5.36
 | Půdorys 1.NP | ZELEZOBETONOVÁ KCE | Betonářské práce | 0 | 0 | @452@ | 1402Slo0000000228 | m3 | Sloup | EXISTING | yes | 0.4 | 0.4 | 0.16 | 0.536 | 0.536 | 3.35 | 5.36
 | Půdorys 1.NP | ZELEZOBETONOVÁ KCE | Betonářské práce | 0 | 0 | @452@ | 1402Slo0000000014 | m3 | Sloup | EXISTING | yes | 0.4 | 0.4 | 0.16 | 0.536 | 0.536 | 3.35 | 5.36
 | Půdorys 1.NP | ZELEZOBETONOVÁ KCE | Betonářské práce | 0 | 0 | @452@ | 1402Slo0000000259 | m3 | Sloup | EXISTING | yes | 0.4 | 0.4 | 0.16 | 0.536 | 0.536 | 3.35 | 5.36
 | Půdorys 1.NP | ZELEZOBETONOVÁ KCE | Betonářské práce | 0 | 0 | @452@ | 1402Slo0000000262 | m3 | Sloup | EXISTING | yes | 0.4 | 0.4 | 0.16 | 0.536 | 0.536 | 3.35 | 5.36
 | Půdorys 1.NP | ZELEZOBETONOVÁ KCE | Betonářské práce | 0 | 0 | @452@ | 1402Slo0000000230 | m3 | Sloup | EXISTING | yes | 0.4 | 0.4 | 0.16 | 0.536 | 0.536 | 3.35 | 5.36
 | Půdorys 1.NP | ZELEZOBETONOVÁ KCE | Betonářské práce | 0 | 0 | @452@ | 1402Slo0798453488 | m3 | Sloup | EXISTING | yes | 0.4 | 0.4 | 0.16 | 0.536 | 0.536 | 3.35 | 5.36
 | Půdorys 1.NP | ZELEZOBETONOVÁ KCE | Betonářské práce | 0 | 0 | @452@ | 1402Slo0798453495 | m3 | Sloup | EXISTING | yes | 0.4 | 0.4 | 0.16 | 0.536 | 0.536 | 3.35 | 5.36
 | Půdorys 1.NP | ZELEZOBETONOVÁ KCE | Betonářské práce | 0 | 0 | @452@ | 1402Slo0000000049 | m3 | Sloup | EXISTING | yes | 0.4 | 0.4 | 0.16 | 0.536 | 0.536 | 3.35 | 5.36
 | Půdorys 1.NP | ZELEZOBETONOVÁ KCE | Betonářské práce | 0 | 0 | @452@ | 1402Slo0000000050 | m3 | Sloup | EXISTING | yes | 0.4 | 0.4 | 0.16 | 0.536 | 0.536 | 3.35 | 5.36
 | Půdorys 1.NP | ZELEZOBETONOVÁ KCE | Betonářské práce | 0 | 0 | @452@ | 1402Slo0000000267 | m3 | Sloup | EXISTING | yes | 0.4 | 0.4 | 0.16 | 0.536 | 0.536 | 3.35 | 5.36
 | Půdorys 1.NP | ZELEZOBETONOVÁ KCE | Betonářské práce | 0 | 0 | @452@ | 1402Slo0000000240 | m3 | Sloup | EXISTING | yes | 0.4 | 0.4 | 0.16 | 0.536 | 0.536 | 3.35 | 5.36
 | Půdorys 1.NP | ZELEZOBETONOVÁ KCE | Betonářské práce | 0 | 0 | @452@ | 1402Slo0000000237 | m3 | Sloup | EXISTING | yes | 0.4 | 0.4 | 0.16 | 0.536 | 0.536 | 3.35 | 5.36
 | Půdorys 1.NP | ZELEZOBETONOVÁ KCE | Betonářské práce | 0 | 0 | @452@ | 1402Slo0798453497 | m3 | Sloup | EXISTING | yes | 0.4 | 0.4 | 0.16 | 0.536 | 0.536 | 3.35 | 5.36
 | Půdorys 1.NP | ZELEZOBETONOVÁ KCE | Betonářské práce | 0 | 0 | @452@ | 1402Slo0798453500 | m3 | Sloup | EXISTING | yes | 0.4 | 0.4 | 0.16 | 0.536 | 0.536 | 3.35 | 5.36
 | Půdorys 1.NP | ZELEZOBETONOVÁ KCE | Betonářské práce | 0 | 0 | @452@ | 1402Slo0798453501 | m3 | Sloup | EXISTING | yes | 0.4 | 0.4 | 0.16 | 0.536 | 0.536 | 3.35 | 5.36
 | Půdorys 1.NP | ZELEZOBETONOVÁ KCE | Betonářské práce | 0 | 0 | @452@ | 1402Slo0000000229 | m3 | Sloup | EXISTING | yes | 0.4 | 0.4 | 0.16 | 0.536 | 0.536 | 3.35 | 5.36
 | Půdorys 1.NP | ZELEZOBETONOVÁ KCE | Betonářské práce | 0 | 0 | @452@ | 1402Slo0000000232 | m3 | Sloup | EXISTING | yes | 0.4 | 0.4 | 0.16 | 0.536 | 0.536 | 3.35 | 5.36
 | Půdorys 1.NP | ZELEZOBETONOVÁ KCE | Betonářské práce | 0 | 0 | @452@ | 1402Slo0000000269 | m3 | Sloup | EXISTING | yes | 0.4 | 0.4 | 0.16 | 0.536 | 0.536 | 3.35 | 5.36
 | Půdorys 1.NP | ZELEZOBETONOVÁ KCE | Betonářské práce | 0 | 0 | @452@ | 1402Slo0000000271 | m3 | Sloup | EXISTING | yes | 0.4 | 0.4 | 0.16 | 0.536 | 0.536 | 3.35 | 5.36
 | Půdorys 1.NP | ZELEZOBETONOVÁ KCE | Betonářské práce | 0 | 0 | @452@ | 1402Slo0000000272 | m3 | Sloup | EXISTING | yes | 0.4 | 0.4 | 0.16 | 0.536 | 0.536 | 3.35 | 5.36
 | Půdorys 1.NP | ZELEZOBETONOVÁ KCE | Betonářské práce | 0 | 0 | @452@ | 1402Slo0000000239 | m3 | Sloup | EXISTING | yes | 0.4 | 0.4 | 0.16 | 0.536 | 0.536 | 3.35 | 5.36
 | Půdorys 1.NP | ZELEZOBETONOVÁ KCE | Betonářské práce | 0 | 0 | @452@ | 1402Slo0000000004 | m3 | Sloup | EXISTING | yes | 0.4 | 0.4 | 0.16 | 0.536 | 0.536 | 3.35 | 5.36
 | Půdorys 1.NP | ZELEZOBETONOVÁ KCE | Betonářské práce | 0 | 0 | @452@ | 1402Slo0000000055 | m3 | Sloup | EXISTING | yes | 0.4 | 0.4 | 0.16 | 0.536 | 0.536 | 3.35 | 5.36
 | Půdorys 1.NP | ZELEZOBETONOVÁ KCE | Betonářské práce | 0 | 0 | @452@ | 1402Slo0000000022 | m3 | Sloup | EXISTING | yes | 0.4 | 0.4 | 0.16 | 0.536 | 0.536 | 3.35 | 5.36
 | Půdorys 1.NP | ZELEZOBETONOVÁ KCE | Betonářské práce | 0 | 0 | @452@ | 1402Slo0000000024 | m3 | Sloup | EXISTING | yes | 0.4 | 0.4 | 0.16 | 0.536 | 0.536 | 3.35 | 5.36
 | Půdorys 1.NP | ZELEZOBETONOVÁ KCE | Betonářské práce | 0 | 0 | @452@ | 1402Slo0000000020 | m3 | Sloup | EXISTING | yes | 0.4 | 0.4 | 0.16 | 0.536 | 0.536 | 3.35 | 5.36
 | Půdorys 1.NP | ZELEZOBETONOVÁ KCE | Betonářské práce | 0 | 0 | @452@ | 1402Slo0000000236 | m3 | Sloup | EXISTING | yes | 0.4 | 0.4 | 0.16 | 0.536 | 0.536 | 3.35 | 5.36
 | Půdorys 1.NP | ZELEZOBETONOVÁ KCE | Betonářské práce | 0 | 0 | @452@ | 1402Slo0000000234 | m3 | Sloup | EXISTING | yes | 0.4 | 0.4 | 0.16 | 0.536 | 0.536 | 3.35 | 5.36
 | Půdorys 1.NP | ZELEZOBETONOVÁ KCE | Betonářské práce | 0 | 0 | @452@ | 1402Slo0000000238 | m3 | Sloup | EXISTING | yes | 0.4 | 0.4 | 0.16 | 0.536 | 0.536 | 3.35 | 5.36
 | Půdorys 1.NP | ZELEZOBETONOVÁ KCE | Betonářské práce | 0 | 0 | @452@ | 1402Slo0000000233 | m3 | Sloup | EXISTING | yes | 0.4 | 0.4 | 0.16 | 0.536 | 0.536 | 3.35 | 5.36
 | Půdorys 1.NP | ZELEZOBETONOVÁ KCE | Betonářské práce | 0 | 0 | @452@ | 1402Slo0000000235 | m3 | Sloup | EXISTING | yes | 0.4 | 0.4 | 0.16 | 0.536 | 0.536 | 3.35 | 5.36
 | Půdorys 2.NP | ZELEZOBETONOVÁ KCE | Betonářské práce | 0 | 0 | @452@ | 1502Slo0000000753 | m3 | Sloup | EXISTING | yes | 0.4 | 0.4 | 0.16 | 0.536 | 0.536 | 3.35 | 5.36
 | Půdorys 2.NP | ZELEZOBETONOVÁ KCE | Betonářské práce | 0 | 0 | @452@ | 1502Slo0000000757 | m3 | Sloup | EXISTING | yes | 0.4 | 0.4 | 0.16 | 0.536 | 0.536 | 3.35 | 5.36
 | Půdorys 2.NP | ZELEZOBETONOVÁ KCE | Betonářské práce | 0 | 0 | @452@ | 1502Slo0000000759 | m3 | Sloup | EXISTING | yes | 0.4 | 0.4 | 0.16 | 0.536 | 0.536 | 3.35 | 5.36
 | Půdorys 2.NP | ZELEZOBETONOVÁ KCE | Betonářské práce | 0 | 0 | @452@ | 1502Slo0000000761 | m3 | Sloup | EXISTING | yes | 0.4 | 0.4 | 0.16 | 0.536 | 0.536 | 3.35 | 5.36
 | Půdorys 2.NP | ZELEZOBETONOVÁ KCE | Betonářské práce | 0 | 0 | @452@ | 1502Slo0000004283 | m3 | Sloup | EXISTING | yes | 0.4 | 0.4 | 0.16 | 0.536 | 0.536 | 3.35 | 5.36
 | Půdorys 2.NP | ZELEZOBETONOVÁ KCE | Betonářské práce | 0 | 0 | @452@ | 1502Slo0000000505 | m3 | Sloup | EXISTING | yes | 0.4 | 0.4 | 0.16 | 0.536 | 0.536 | 3.35 | 5.36
 | Půdorys 2.NP | ZELEZOBETONOVÁ KCE | Betonářské práce | 0 | 0 | @452@ | 1502Slo0000001129 | m3 | Sloup | EXISTING | yes | 0.4 | 0.4 | 0.16 | 0.536 | 0.536 | 3.35 | 5.36
 | Půdorys 2.NP | ZELEZOBETONOVÁ KCE | Betonářské práce | 0 | 0 | @452@ | 1502Slo0000000953 | m3 | Sloup | EXISTING | yes | 0.4 | 0.4 | 0.16 | 0.536 | 0.536 | 3.35 | 5.36
 | Půdorys 2.NP | ZELEZOBETONOVÁ KCE | Betonářské práce | 0 | 0 | @452@ | 1502Slo0000002317 | m3 | Sloup | EXISTING | yes | 0.4 | 0.4 | 0.16 | 0.536 | 0.536 | 3.35 | 5.36
 | Půdorys 2.NP | ZELEZOBETONOVÁ KCE | Betonářské práce | 0 | 0 | @452@ | 1502Slo0000002286 | m3 | Sloup | EXISTING | yes | 0.4 | 0.4 | 0.16 | 0.536 | 0.536 | 3.35 | 5.36
 | Půdorys 2.NP | ZELEZOBETONOVÁ KCE | Betonářské práce | 0 | 0 | @452@ | 1502Slo0000004282 | m3 | Sloup | EXISTING | yes | 0.4 | 0.4 | 0.16 | 0.536 | 0.536 | 3.35 | 5.36
 | Půdorys 1.PP | ZELEZOBETONOVÁ KCE | Betonářské práce | 0 | 0 | @452@ | 1352Slo0000002439 | m3 | Sloup | EXISTING | yes | 0.4 | 0.4 | 0.16 | 0.536 | 0.536 | 3.35 | 5.36
 | Půdorys 1.PP | ZELEZOBETONOVÁ KCE | Betonářské práce | 0 | 0 | @452@ | 1352Slo0000002466 | m3 | Sloup | EXISTING | yes | 0.4 | 0.4 | 0.16 | 0.536 | 0.536 | 3.35 | 5.36
 | Půdorys 1.PP | ZELEZOBETONOVÁ KCE | Betonářské práce | 0 | 0 | @452@ | 1352Slo0000002454 | m3 | Sloup | EXISTING | yes | 0.4 | 0.4 | 0.16 | 0.536 | 0.536 | 3.35 | 5.36
 | Půdorys 1.PP | ZELEZOBETONOVÁ KCE | Betonářské práce | 0 | 0 | @452@ | 1352Slo0000002442 | m3 | Sloup | EXISTING | yes | 0.4 | 0.4 | 0.16 | 0.536 | 0.536 | 3.35 | 5.36
 | Půdorys 1.PP | ZELEZOBETONOVÁ KCE | Betonářské práce | 0 | 0 | @452@ | 1352Slo0000002427 | m3 | Sloup | EXISTING | yes | 0.6 | 0.6 | 0.36 | 1.206 | 1.206 | 3.35 | 8.04
 | Půdorys 1.PP | ZELEZOBETONOVÁ KCE | Betonářské práce | 0 | 0 | @452@ | 1352Slo0000002415 | m3 | Sloup | EXISTING | yes | 0.6 | 0.6 | 0.36 | 1.206 | 1.206 | 3.35 | 8.04
 | Půdorys 1.PP | ZELEZOBETONOVÁ KCE | Betonářské práce | 0 | 0 | @452@ | 1352Slo0000002382 | m3 | Sloup | EXISTING | yes | 0.6 | 0.6 | 0.36 | 1.206 | 1.206 | 3.35 | 8.04
 | Půdorys 1.PP | ZELEZOBETONOVÁ KCE | Betonářské práce | 0 | 0 | @452@ | 1352Slo0000002376 | m3 | Sloup | EXISTING | yes | 0.6 | 0.6 | 0.36 | 1.206 | 1.206 | 3.35 | 8.04
 | Půdorys 1.PP | ZELEZOBETONOVÁ KCE | Betonářské práce | 0 | 0 | @452@ | 1352Slo0000002361 | m3 | Sloup | EXISTING | yes | 0.6 | 0.6 | 0.36 | 1.206 | 1.206 | 3.35 | 8.04
 | Půdorys 1.PP | ZELEZOBETONOVÁ KCE | Betonářské práce | 0 | 0 | @452@ | 1352Slo0000002358 | m3 | Sloup | EXISTING | yes | 0.6 | 0.6 | 0.36 | 1.206 | 1.206 | 3.35 | 8.04
 | Půdorys 1.PP | ZELEZOBETONOVÁ KCE | Betonářské práce | 0 | 0 | @452@ | 1352Slo0000002349 | m3 | Sloup | EXISTING | yes | 0.6 | 0.6 | 0.36 | 1.206 | 1.206 | 3.35 | 8.04
 | Půdorys 1.PP | ZELEZOBETONOVÁ KCE | Betonářské práce | 0 | 0 | @452@ | 1352Slo0000002346 | m3 | Sloup | EXISTING | yes | 0.6 | 0.6 | 0.36 | 1.206 | 1.206 | 3.35 | 8.04
 | Půdorys 1.PP | ZELEZOBETONOVÁ KCE | Betonářské práce | 0 | 0 | @452@ | 1352Slo0000003571 | m3 | Sloup | EXISTING | yes | 0.4 | 0.4 | 0.16 | 0.536 | 0.536 | 3.35 | 5.36
 | Půdorys 1.PP | ZELEZOBETONOVÁ KCE | Betonářské práce | 0 | 0 | @452@ | 1352Slo0000002421 | m3 | Sloup | EXISTING | yes | 0.6 | 0.6 | 0.36 | 1.206 | 1.206 | 3.35 | 8.04
 | Půdorys 1.PP | ZELEZOBETONOVÁ KCE | Betonářské práce | 0 | 0 | @452@ | 1352Slo0000003640 | m3 | Sloup | EXISTING | yes | 0.6 | 0.4 | 0.24 | 0.804 | 0.804 | 3.35 | 6.7
 | Půdorys 1.PP | ZELEZOBETONOVÁ KCE | Betonářské práce | 0 | 0 | @452@ | 1352Slo0000002409 | m3 | Sloup | EXISTING | yes | 0.6 | 0.6 | 0.36 | 1.206 | 1.206 | 3.35 | 8.04
 | Půdorys 1.PP | ZELEZOBETONOVÁ KCE | Betonářské práce | 0 | 0 | @452@ | 1352Slo0000003576 | m3 | Sloup | EXISTING | yes | 0.4 | 0.4 | 0.16 | 0.536 | 0.536 | 3.35 | 5.36
 | Půdorys 1.PP | ZELEZOBETONOVÁ KCE | Betonářské práce | 0 | 0 | @452@ | 1352Slo0000002379 | m3 | Sloup | EXISTING | yes | 0.6 | 0.6 | 0.36 | 1.206 | 1.206 | 3.35 | 8.04
 | Půdorys 1.PP | ZELEZOBETONOVÁ KCE | Betonářské práce | 0 | 0 | @452@ | 1352Slo0798466222 | m3 | Sloup | EXISTING | yes | 0.6 | 0.6 | 0.36 | 1.098 | 1.098 | 3.05 | 7.32
 | Půdorys 1.PP | ZELEZOBETONOVÁ KCE | Betonářské práce | 0 | 0 | @452@ | 1352Slo0798450695 | m3 | Sloup | EXISTING | yes | 0.25 | 0.25 | 0.062 | 0.225 | 0.225 | 3.6 | 3.599
 | Půdorys 1.PP | ZELEZOBETONOVÁ KCE | Betonářské práce | 0 | 0 | @452@ | 1352Slo0000002430 | m3 | Sloup | EXISTING | yes | 0.6 | 0.6 | 0.36 | 1.206 | 1.206 | 3.35 | 8.04
 | Půdorys 1.PP | ZELEZOBETONOVÁ KCE | Betonářské práce | 0 | 0 | @452@ | 1352Slo0000000009 | m3 | Sloup | EXISTING | yes | 0.6 | 0.6 | 0.36 | 1.206 | 1.206 | 3.35 | 8.04
 | Půdorys 1.PP | ZELEZOBETONOVÁ KCE | Betonářské práce | 0 | 0 | @452@ | 1352Slo0000012666 | m3 | Sloup | EXISTING | yes | 0.4 | 0.6 | 0.24 | 0.804 | 0.804 | 3.35 | 6.7
 | Půdorys 1.PP | ZELEZOBETONOVÁ KCE | Betonářské práce | 0 | 0 | @452@ | 1352Slo0000002397 | m3 | Sloup | EXISTING | yes | 0.6 | 0.6 | 0.36 | 1.206 | 1.206 | 3.35 | 8.04
 | Půdorys 1.PP | ZELEZOBETONOVÁ KCE | Betonářské práce | 0 | 0 | @452@ | 1352Slo0000002388 | m3 | Sloup | EXISTING | yes | 0.6 | 0.6 | 0.36 | 1.206 | 1.206 | 3.35 | 8.04
 | Půdorys 1.PP | ZELEZOBETONOVÁ KCE | Betonářské práce | 0 | 0 | @452@ | 1352Slo0000002403 | m3 | Sloup | EXISTING | yes | 0.6 | 0.6 | 0.36 | 1.206 | 1.206 | 3.35 | 8.04
 | Půdorys 1.PP | ZELEZOBETONOVÁ KCE | Betonářské práce | 0 | 0 | @452@ | 1352Slo0000002457 | m3 | Sloup | EXISTING | yes | 0.4 | 0.4 | 0.16 | 0.536 | 0.536 | 3.35 | 5.36
 | Půdorys 1.PP | ZELEZOBETONOVÁ KCE | Betonářské práce | 0 | 0 | @452@ | 1352Slo0000002400 | m3 | Sloup | EXISTING | yes | 0.6 | 0.6 | 0.36 | 1.206 | 1.206 | 3.35 | 8.04
 | Půdorys 1.PP | ZELEZOBETONOVÁ KCE | Betonářské práce | 0 | 0 | @452@ | 1352Slo0000002460 | m3 | Sloup | EXISTING | yes | 0.4 | 0.4 | 0.16 | 0.536 | 0.536 | 3.35 | 5.36
 | Půdorys 1.PP | ZELEZOBETONOVÁ KCE | Betonářské práce | 0 | 0 | @452@ | 1352Slo0000002406 | m3 | Sloup | EXISTING | yes | 0.6 | 0.6 | 0.36 | 1.206 | 1.206 | 3.35 | 8.04
 | Půdorys 1.PP | ZELEZOBETONOVÁ KCE | Betonářské práce | 0 | 0 | @452@ | 1352Slo0000002418 | m3 | Sloup | EXISTING | yes | 0.6 | 0.6 | 0.36 | 1.206 | 1.206 | 3.35 | 8.04
 | Půdorys 1.PP | ZELEZOBETONOVÁ KCE | Betonářské práce | 0 | 0 | @452@ | 1352Slo0000002463 | m3 | Sloup | EXISTING | yes | 0.4 | 0.4 | 0.16 | 0.536 | 0.536 | 3.35 | 5.36
 | Půdorys 1.PP | ZELEZOBETONOVÁ KCE | Betonářské práce | 0 | 0 | @452@ | 1352Slo0000002487 | m3 | Sloup | EXISTING | yes | 0.6 | 0.4 | 0.24 | 0.804 | 0.804 | 3.35 | 6.7
 | Půdorys 1.PP | ZELEZOBETONOVÁ KCE | Betonářské práce | 0 | 0 | @452@ | 1352Slo0000002394 | m3 | Sloup | EXISTING | yes | 0.6 | 0.6 | 0.36 | 1.206 | 1.206 | 3.35 | 8.04
 | Půdorys 1.PP | ZELEZOBETONOVÁ KCE | Betonářské práce | 0 | 0 | @452@ | 1352Slo0000002475 | m3 | Sloup | EXISTING | yes | 0.6 | 0.4 | 0.24 | 0.804 | 0.804 | 3.35 | 6.7
 | Půdorys 1.PP | ZELEZOBETONOVÁ KCE | Betonářské práce | 0 | 0 | @452@ | 1352Slo0000002367 | m3 | Sloup | EXISTING | yes | 0.6 | 0.6 | 0.36 | 1.206 | 1.206 | 3.35 | 8.04
 | Půdorys 1.PP | ZELEZOBETONOVÁ KCE | Betonářské práce | 0 | 0 | @452@ | 1352Slo0000000003 | m3 | Sloup | EXISTING | yes | 0.6 | 0.6 | 0.36 | 1.206 | 1.206 | 3.35 | 8.04
 | Půdorys 1.PP | ZELEZOBETONOVÁ KCE | Betonářské práce | 0 | 0 | @452@ | 1352Slo0000000027 | m3 | Sloup | EXISTING | yes | 0.6 | 0.6 | 0.36 | 1.206 | 1.206 | 3.35 | 8.04
 | Půdorys 1.PP | ZELEZOBETONOVÁ KCE | Betonářské práce | 0 | 0 | @452@ | 1352Slo0000002385 | m3 | Sloup | EXISTING | yes | 0.6 | 0.6 | 0.36 | 1.206 | 1.206 | 3.35 | 8.04
 | Půdorys 1.PP | ZELEZOBETONOVÁ KCE | Betonářské práce | 0 | 0 | @452@ | 1352Slo0000012639 | m3 | Sloup | EXISTING | yes | 0.4 | 0.6 | 0.24 | 0.804 | 0.804 | 3.35 | 6.7
 | Půdorys 1.PP | ZELEZOBETONOVÁ KCE | Betonářské práce | 0 | 0 | @452@ | 1352Slo0000003078 | m3 | Sloup | EXISTING | yes | 0.6 | 0.4 | 0.24 | 0.804 | 0.804 | 3.35 | 6.7
 | Půdorys 1.PP | ZELEZOBETONOVÁ KCE | Betonářské práce | 0 | 0 | @452@ | 1352Slo0000000015 | m3 | Sloup | EXISTING | yes | 0.6 | 0.6 | 0.36 | 1.206 | 1.206 | 3.35 | 8.04
 | Půdorys 1.PP | ZELEZOBETONOVÁ KCE | Betonářské práce | 0 | 0 | @452@ | 1352Slo0000002433 | m3 | Sloup | EXISTING | yes | 0.6 | 0.6 | 0.36 | 1.206 | 1.206 | 3.35 | 8.04
 | Půdorys 1.PP | ZELEZOBETONOVÁ KCE | Betonářské práce | 0 | 0 | @452@ | 1352Slo0000002391 | m3 | Sloup | EXISTING | yes | 0.6 | 0.6 | 0.36 | 1.206 | 1.206 | 3.35 | 8.04
 | Půdorys 1.PP | ZELEZOBETONOVÁ KCE | Betonářské práce | 0 | 0 | @452@ | 1352Slo0000012658 | m3 | Sloup | EXISTING | yes | 0.4 | 0.6 | 0.24 | 0.804 | 0.804 | 3.35 | 6.7
 | Půdorys 1.PP | ZELEZOBETONOVÁ KCE | Betonářské práce | 0 | 0 | @452@ | 1352Slo0000000006 | m3 | Sloup | EXISTING | yes | 0.6 | 0.6 | 0.36 | 1.206 | 1.206 | 3.35 | 8.04
 | Půdorys 1.PP | ZELEZOBETONOVÁ KCE | Betonářské práce | 0 | 0 | @452@ | 1352Slo0000002424 | m3 | Sloup | EXISTING | yes | 0.6 | 0.6 | 0.36 | 1.206 | 1.206 | 3.35 | 8.04
 | Půdorys 1.PP | ZELEZOBETONOVÁ KCE | Betonářské práce | 0 | 0 | @452@ | 1352Slo0000000012 | m3 | Sloup | EXISTING | yes | 0.6 | 0.6 | 0.36 | 1.206 | 1.206 | 3.35 | 8.04
 | Půdorys 1.PP | ZELEZOBETONOVÁ KCE | Betonářské práce | 0 | 0 | @452@ | 1352Slo0000000033 | m3 | Sloup | EXISTING | yes | 0.4 | 0.6 | 0.24 | 0.804 | 0.804 | 3.35 | 6.7
 | Půdorys 1.PP | ZELEZOBETONOVÁ KCE | Betonářské práce | 0 | 0 | @452@ | 1352Slo0000002445 | m3 | Sloup | EXISTING | yes | 0.4 | 0.4 | 0.16 | 0.536 | 0.536 | 3.35 | 5.36
 | Půdorys 1.PP | ZELEZOBETONOVÁ KCE | Betonářské práce | 0 | 0 | @452@ | 1352Slo0000002474 | m3 | Sloup | EXISTING | yes | 0.6 | 0.4 | 0.24 | 0.804 | 0.804 | 3.35 | 6.7
 | Půdorys 1.PP | ZELEZOBETONOVÁ KCE | Betonářské práce | 0 | 0 | @452@ | 1352Slo0000002364 | m3 | Sloup | EXISTING | yes | 0.6 | 0.6 | 0.36 | 1.206 | 1.206 | 3.35 | 8.04
 | Půdorys 1.PP | ZELEZOBETONOVÁ KCE | Betonářské práce | 0 | 0 | @452@ | 1352Slo0000002451 | m3 | Sloup | EXISTING | yes | 0.4 | 0.4 | 0.16 | 0.536 | 0.536 | 3.35 | 5.36
 | Půdorys 1.PP | ZELEZOBETONOVÁ KCE | Betonářské práce | 0 | 0 | @452@ | 1352Slo0000002370 | m3 | Sloup | EXISTING | yes | 0.6 | 0.6 | 0.36 | 1.206 | 1.206 | 3.35 | 8.04
 | Půdorys 1.PP | ZELEZOBETONOVÁ KCE | Betonářské práce | 0 | 0 | @452@ | 1352Slo0000002448 | m3 | Sloup | EXISTING | yes | 0.4 | 0.4 | 0.16 | 0.536 | 0.536 | 3.35 | 5.36
 | Půdorys 1.PP | ZELEZOBETONOVÁ KCE | Betonářské práce | 0 | 0 | @452@ | 1352Slo0000002412 | m3 | Sloup | EXISTING | yes | 0.6 | 0.6 | 0.36 | 1.206 | 1.206 | 3.35 | 8.04
 | Půdorys 1.PP | ZELEZOBETONOVÁ KCE | Betonářské práce | 0 | 0 | @452@ | 1352Slo0000002352 | m3 | Sloup | EXISTING | yes | 0.6 | 0.6 | 0.36 | 1.206 | 1.206 | 3.35 | 8.04
 | Půdorys 1.PP | ZELEZOBETONOVÁ KCE | Betonářské práce | 0 | 0 | @452@ | 1352Slo0000002355 | m3 | Sloup | EXISTING | yes | 0.6 | 0.6 | 0.36 | 1.206 | 1.206 | 3.35 | 8.04
 | Půdorys 1.PP | ZELEZOBETONOVÁ KCE | Betonářské práce | 0 | 0 | @452@ | 1352Slo0000002473 | m3 | Sloup | EXISTING | yes | 0.6 | 0.4 | 0.24 | 0.804 | 0.804 | 3.35 | 6.7
 | Půdorys 1.PP | ZELEZOBETONOVÁ KCE | Betonářské práce | 0 | 0 | @452@ | 1352Slo0000002472 | m3 | Sloup | EXISTING | yes | 0.6 | 0.4 | 0.24 | 0.804 | 0.804 | 3.35 | 6.7
 | Půdorys 1.PP | ZELEZOBETONOVÁ KCE | Betonářské práce | 0 | 0 | @452@ | 1352Slo0000002469 | m3 | Sloup | EXISTING | yes | 0.6 | 0.4 | 0.24 | 0.804 | 0.804 | 3.35 | 6.7
 | Půdorys 1.PP | ZELEZOBETONOVÁ KCE | Betonářské práce | 0 | 0 | @452@ | 1352Slo0000002343 | m3 | Sloup | EXISTING | yes | 0.6 | 0.6 | 0.36 | 1.206 | 1.206 | 3.35 | 8.04
 | Půdorys 1.PP | ZELEZOBETONOVÁ KCE | Betonářské práce | 0 | 0 | @452@ | 1352Slo0000002481 | m3 | Sloup | EXISTING | yes | 0.6 | 0.4 | 0.24 | 0.804 | 0.804 | 3.35 | 6.7
 | Půdorys 1.PP | ZELEZOBETONOVÁ KCE | Betonářské práce | 0 | 0 | @452@ | 1352Slo0000002480 | m3 | Sloup | EXISTING | yes | 0.6 | 0.4 | 0.24 | 0.804 | 0.804 | 3.35 | 6.7
 | Půdorys 1.PP | ZELEZOBETONOVÁ KCE | Betonářské práce | 0 | 0 | @452@ | 1352Slo0000002479 | m3 | Sloup | EXISTING | yes | 0.6 | 0.4 | 0.24 | 0.804 | 0.804 | 3.35 | 6.7
 | Půdorys 1.PP | ZELEZOBETONOVÁ KCE | Betonářské práce | 0 | 0 | @452@ | 1352Slo0000000024 | m3 | Sloup | EXISTING | yes | 0.6 | 0.6 | 0.36 | 1.206 | 1.206 | 3.35 | 8.04
 | Půdorys 1.PP | ZELEZOBETONOVÁ KCE | Betonářské práce | 0 | 0 | @452@ | 1352Slo0000012665 | m3 | Sloup | EXISTING | yes | 0.4 | 0.6 | 0.24 | 0.804 | 0.804 | 3.35 | 6.7
 | Půdorys 1.PP | ZELEZOBETONOVÁ KCE | Betonářské práce | 0 | 0 | @452@ | 1352Slo0000000021 | m3 | Sloup | EXISTING | yes | 0.6 | 0.6 | 0.36 | 1.206 | 1.206 | 3.35 | 8.04
 | Půdorys 1.PP | ZELEZOBETONOVÁ KCE | Betonářské práce | 0 | 0 | @452@ | 1352Slo0000000018 | m3 | Sloup | EXISTING | yes | 0.6 | 0.6 | 0.36 | 1.206 | 1.206 | 3.35 | 8.04
 | Půdorys 1.PP | ZELEZOBETONOVÁ KCE | Betonářské práce | 0 | 0 | @452@ | 1352Slo0000012663 | m3 | Sloup | EXISTING | yes | 0.4 | 0.6 | 0.24 | 0.804 | 0.804 | 3.35 | 6.7
 | Půdorys 1.PP | ZELEZOBETONOVÁ KCE | Betonářské práce | 0 | 0 | @452@ | 1352Slo0000012664 | m3 | Sloup | EXISTING | yes | 0.4 | 0.6 | 0.24 | 0.804 | 0.804 | 3.35 | 6.7
 | Půdorys 1.PP | ZELEZOBETONOVÁ KCE | Betonářské práce | 0 | 0 | @452@ | 1352Slo0000012599 | m3 | Sloup | EXISTING | yes | 0.4 | 0.6 | 0.24 | 0.804 | 0.804 | 3.35 | 6.7
 | Půdorys 1.PP | ZELEZOBETONOVÁ KCE | Betonářské práce | 0 | 0 | @452@ | 1352Slo0000012634 | m3 | Sloup | EXISTING | yes | 0.4 | 0.6 | 0.24 | 0.804 | 0.804 | 3.35 | 6.7
 | Půdorys 1.PP | ZELEZOBETONOVÁ KCE | Betonářské práce | 0 | 0 | @452@ | 1352Slo0000002373 | m3 | Sloup | EXISTING | yes | 0.6 | 0.6 | 0.36 | 1.206 | 1.206 | 3.35 | 8.04
 | Půdorys 1.PP | ZELEZOBETONOVÁ KCE | Betonářské práce | 0 | 0 | @452@ | 1352Slo0000002476 | m3 | Sloup | EXISTING | yes | 0.6 | 0.4 | 0.24 | 0.804 | 0.804 | 3.35 | 6.7
 | Půdorys 1.PP | ZELEZOBETONOVÁ KCE | Betonářské práce | 0 | 0 | @452@ | 1352Slo0000002477 | m3 | Sloup | EXISTING | yes | 0.6 | 0.4 | 0.24 | 0.804 | 0.804 | 3.35 | 6.7
 | Půdorys 1.PP | ZELEZOBETONOVÁ KCE | Betonářské práce | 0 | 0 | @452@ | 1352Slo0000002478 | m3 | Sloup | EXISTING | yes | 0.6 | 0.4 | 0.24 | 0.804 | 0.804 | 3.35 | 6.7
 | Půdorys 1.PP | ZELEZOBETONOVÁ KCE | Betonářské práce | 0 | 0 | @452@ | 1352Slo0000012667 | m3 | Sloup | EXISTING | yes | 0.4 | 0.6 | 0.24 | 0.804 | 0.804 | 3.35 | 6.7
 | Půdorys 1.PP | ZELEZOBETONOVÁ KCE | Betonářské práce | 0 | 0 | @452@ | 1352Slo0000000030 | m3 | Sloup | EXISTING | yes | 0.6 | 0.6 | 0.36 | 1.206 | 1.206 | 3.35 | 8.04
 | Půdorys 1.PP | ZELEZOBETONOVÁ KCE | Betonářské práce | 200 |  |  | 1364Slo0798495236 | m3 | Sloup | NEW | yes | 0.4 | 0.4 | 0.16 | 0.52 | 0.52 | 3.25 | 5.2 | NEMSOK - Kód prvku: SL02.02.0001; Třída pevnosti ocele: B500B; Podlaží: 1.PP; Požární odolnost: R 45DP1; Třída pevnosti betonu: C25/30-XC1; Krytí výztuže: 35mm; Funkce (venkovní): Ne; Statická funkce: Ano
 | Půdorys 1.PP | ZELEZOBETONOVÁ KCE | Betonářské práce | 200 |  |  | 1364Slo0798495648 | m3 | Sloup | NEW | yes | 0.4 | 0.4 | 0.16 | 0.52 | 0.52 | 3.25 | 5.2 | NEMSOK - Kód prvku: SL02.02.0002; Třída pevnosti ocele: B500B; Podlaží: 1.PP; Požární odolnost: R 45DP1; Třída pevnosti betonu: C25/30-XC1; Krytí výztuže: 35mm; Funkce (venkovní): Ne; Statická funkce: Ano
 | Půdorys 1.NP | ZELEZOBETONOVÁ KCE | Betonářské práce | 0 | 0 | @452@ | 1452Slo0000002248 | m3 | Sloup | EXISTING | yes | 0.4 | 0.4 | 0.16 | 0.536 | 0.536 | 3.35 | 5.36
 | Půdorys 1.NP | ZELEZOBETONOVÁ KCE | Betonářské práce | 0 | 0 | @452@ | 1452Slo0000002843 | m3 | Sloup | EXISTING | yes | 0.4 | 0.4 | 0.16 | 0.536 | 0.536 | 3.35 | 5.36
 | Půdorys 1.NP | ZELEZOBETONOVÁ KCE | Betonářské práce | 0 | 0 | @452@ | 1452Slo0000002847 | m3 | Sloup | EXISTING | yes | 0.4 | 0.4 | 0.16 | 0.536 | 0.536 | 3.35 | 5.36
 | Půdorys 1.NP | ZELEZOBETONOVÁ KCE | Betonářské práce | 0 | 0 | @452@ | 1452Slo0000002875 | m3 | Sloup | EXISTING | yes | 0.6 | 0.6 | 0.36 | 1.206 | 1.206 | 3.35 | 8.04
 | Půdorys 1.NP | ZELEZOBETONOVÁ KCE | Betonářské práce | 0 | 0 | @452@ | 1452Slo0000002897 | m3 | Sloup | EXISTING | yes | 0.6 | 0.6 | 0.36 | 1.206 | 1.206 | 3.35 | 8.04
 | Půdorys 1.NP | ZELEZOBETONOVÁ KCE | Betonářské práce | 0 | 0 | @452@ | 1452Slo0000002917 | m3 | Sloup | EXISTING | yes | 0.4 | 0.4 | 0.16 | 0.536 | 0.536 | 3.35 | 5.36
 | Půdorys 1.NP | ZELEZOBETONOVÁ KCE | Betonářské práce | 0 | 0 | @452@ | 1452Slo0000002941 | m3 | Sloup | EXISTING | yes | 0.6 | 0.4 | 0.24 | 0.804 | 0.804 | 3.35 | 6.7
 | Půdorys 1.NP | ZELEZOBETONOVÁ KCE | Betonářské práce | 0 | 0 | @452@ | 1452Slo0000002167 | m3 | Sloup | EXISTING | yes | 0.4 | 0.4 | 0.16 | 0.536 | 0.536 | 3.35 | 5.36
 | Půdorys 1.NP | ZELEZOBETONOVÁ KCE | Betonářské práce | 0 | 0 | @452@ | 1452Slo0000002244 | m3 | Sloup | EXISTING | yes | 0.4 | 0.4 | 0.16 | 0.536 | 0.536 | 3.35 | 5.36
 | Půdorys 1.NP | ZELEZOBETONOVÁ KCE | Betonářské práce | 0 | 0 | @452@ | 1452Slo0000002246 | m3 | Sloup | EXISTING | yes | 0.4 | 0.4 | 0.16 | 0.536 | 0.536 | 3.35 | 5.36
 | Půdorys 1.NP | ZELEZOBETONOVÁ KCE | Betonářské práce | 0 | 0 | @452@ | 1452Slo0000002250 | m3 | Sloup | EXISTING | yes | 0.4 | 0.4 | 0.16 | 0.536 | 0.536 | 3.35 | 5.36
 | Půdorys 1.NP | ZELEZOBETONOVÁ KCE | Betonářské práce | 0 | 0 | @452@ | 1452Slo0000002243 | m3 | Sloup | EXISTING | yes | 0.4 | 0.4 | 0.16 | 0.536 | 0.536 | 3.35 | 5.36
 | Půdorys 1.NP | ZELEZOBETONOVÁ KCE | Betonářské práce | 0 | 0 | @452@ | 1452Slo0000002247 | m3 | Sloup | EXISTING | yes | 0.4 | 0.4 | 0.16 | 0.536 | 0.536 | 3.35 | 5.36
 | Půdorys 1.NP | ZELEZOBETONOVÁ KCE | Betonářské práce | 0 | 0 | @452@ | 1452Slo0000002249 | m3 | Sloup | EXISTING | yes | 0.4 | 0.4 | 0.16 | 0.536 | 0.536 | 3.35 | 5.36
 | Půdorys 1.NP | ZELEZOBETONOVÁ KCE | Betonářské práce | 0 | 0 | @452@ | 1452Slo0000002909 | m3 | Sloup | EXISTING | yes | 0.6 | 0.4 | 0.24 | 0.804 | 0.804 | 3.35 | 6.7
 | Půdorys 1.NP | ZELEZOBETONOVÁ KCE | Betonářské práce | 0 | 0 | @452@ | 1452Slo0000002927 | m3 | Sloup | EXISTING | yes | 0.6 | 0.4 | 0.24 | 0.804 | 0.804 | 3.35 | 6.7
 | Půdorys 1.NP | ZELEZOBETONOVÁ KCE | Betonářské práce | 0 | 0 | @452@ | 1452Slo0000002256 | m3 | Sloup | EXISTING | yes | 0.4 | 0.4 | 0.16 | 0.536 | 0.536 | 3.35 | 5.36
 | Půdorys 1.NP | ZELEZOBETONOVÁ KCE | Betonářské práce | 0 | 0 | @452@ | 1452Slo0000002253 | m3 | Sloup | EXISTING | yes | 0.4 | 0.4 | 0.16 | 0.536 | 0.536 | 3.35 | 5.36
 | Půdorys 1.NP | ZELEZOBETONOVÁ KCE | Betonářské práce | 0 | 0 | @452@ | 1452Slo0000002252 | m3 | Sloup | EXISTING | yes | 0.4 | 0.4 | 0.16 | 0.536 | 0.536 | 3.35 | 5.36
 | Půdorys 1.NP | ZELEZOBETONOVÁ KCE | Betonářské práce | 0 | 0 | @452@ | 1452Slo0000002254 | m3 | Sloup | EXISTING | yes | 0.4 | 0.4 | 0.16 | 0.536 | 0.536 | 3.35 | 5.36
 | Půdorys 1.NP | ZELEZOBETONOVÁ KCE | Betonářské práce | 0 | 0 | @452@ | 1452Slo0000002255 | m3 | Sloup | EXISTING | yes | 0.4 | 0.4 | 0.16 | 0.536 | 0.536 | 3.35 | 5.36
 | Půdorys 1.NP | ZELEZOBETONOVÁ KCE | Betonářské práce | 0 | 0 | @452@ | 1452Slo0798422132 | m3 | Sloup | EXISTING | yes | 0.6 | 0.6 | 0.36 | 1.206 | 1.206 | 3.35 | 8.04
 | Půdorys 1.NP | ZELEZOBETONOVÁ KCE | Betonářské práce | 0 | 0 | @452@ | 1452Slo0000002913 | m3 | Sloup | EXISTING | yes | 0.6 | 0.4 | 0.24 | 0.804 | 0.804 | 3.35 | 6.7
 | Půdorys 1.NP | ZELEZOBETONOVÁ KCE | Betonářské práce | 0 | 0 | @452@ | 1452Slo0000002245 | m3 | Sloup | EXISTING | yes | 0.4 | 0.4 | 0.16 | 0.536 | 0.536 | 3.35 | 5.36
 | Půdorys 1.NP | ZELEZOBETONOVÁ KCE | Betonářské práce | 0 | 0 | @452@ | 1452Slo0000002939 | m3 | Sloup | EXISTING | yes | 0.6 | 0.4 | 0.24 | 0.804 | 0.804 | 3.35 | 6.7
 | Půdorys 1.NP | ZELEZOBETONOVÁ KCE | Betonářské práce | 0 | 0 | @452@ | 1452Slo0000002877 | m3 | Sloup | EXISTING | yes | 0.6 | 0.6 | 0.36 | 1.206 | 1.206 | 3.35 | 8.04
 | Půdorys 1.NP | ZELEZOBETONOVÁ KCE | Betonářské práce | 0 | 0 | @452@ | 1452Slo0000002937 | m3 | Sloup | EXISTING | yes | 0.4 | 0.4 | 0.16 | 0.536 | 0.536 | 3.35 | 5.36
 | Půdorys 1.NP | ZELEZOBETONOVÁ KCE | Betonářské práce | 0 | 0 | @452@ | 1452Slo0000002837 | m3 | Sloup | EXISTING | yes | 0.4 | 0.4 | 0.16 | 0.536 | 0.536 | 3.35 | 5.36
 | Půdorys 1.NP | ZELEZOBETONOVÁ KCE | Betonářské práce |  |  |  | 1452Slo1096107414 | m3 | Sloup | EXISTING | yes | 0.4 | 0.4 | 0.16 | 0.536 | 0.536 | 3.35 | 5.36
 | Půdorys 1.NP | ZELEZOBETONOVÁ KCE | Betonářské práce |  |  |  | 1452Slo1096107435 | m3 | Sloup | EXISTING | yes | 0.4 | 0.4 | 0.16 | 0.536 | 0.536 | 3.35 | 5.36
 | Půdorys 1.NP | ZELEZOBETONOVÁ KCE | Betonářské práce |  |  |  | 1452Slo1096107452 | m3 | Sloup | EXISTING | yes | 0.4 | 0.4 | 0.16 | 0.536 | 0.536 | 3.35 | 5.36
 | Půdorys 1.NP | ZELEZOBETONOVÁ KCE | Betonářské práce | 0 | 0 | @452@ | 1452Slo0000002935 | m3 | Sloup | EXISTING | yes | 0.6 | 0.6 | 0.36 | 1.206 | 1.206 | 3.35 | 8.04
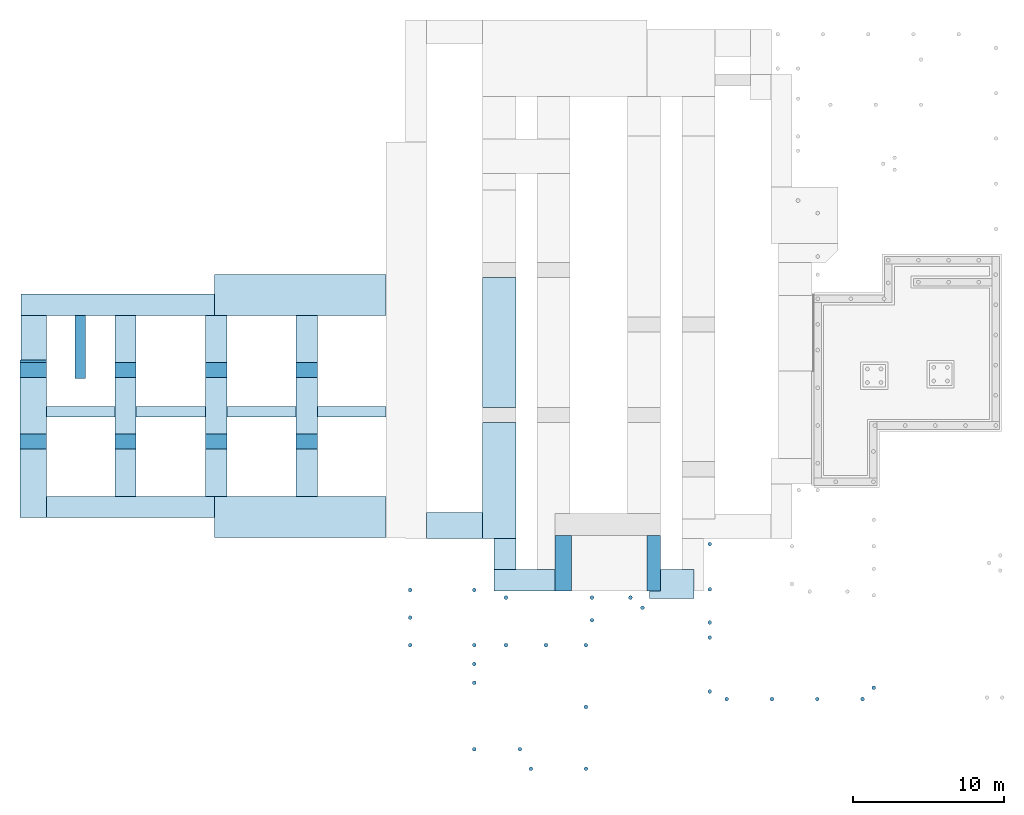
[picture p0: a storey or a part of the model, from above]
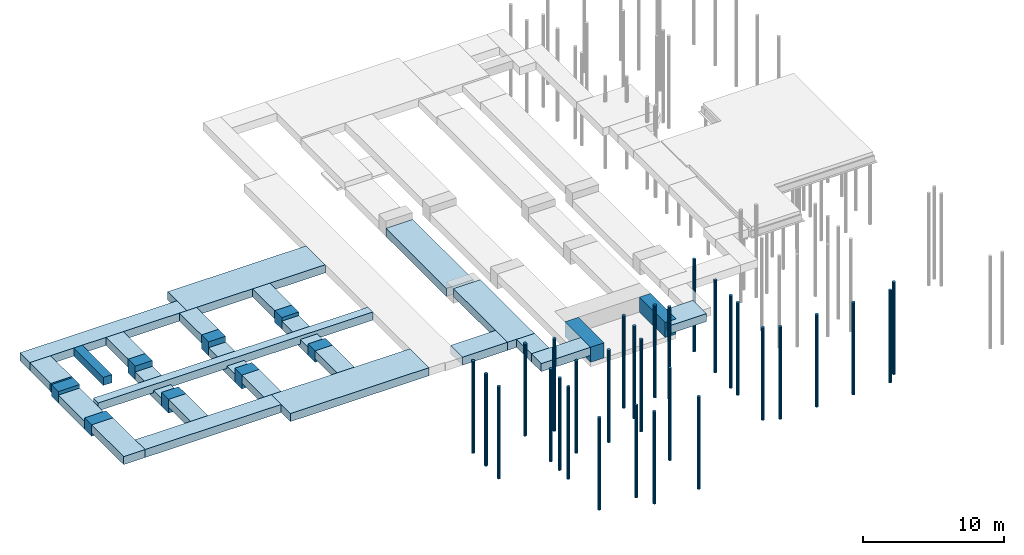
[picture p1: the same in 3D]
Properties of the parts of a building model (IFC4), part 4 of 45

# IfcColumn (605)
Name | In | Material = Materiál | Práce | Stupeň vyztužení | Číslo parkovacího místa | LOD | Allright_Stavebni_dil_ID | Jednotka | Název_objektu | Status | LoadBearing | Width (m) | Depth (m) | CrossSectionArea (m2) | GrossVolume (m3) | NetVolume (m3) | Length (m) | OuterSurfaceArea (m2)
 | Půdorys 1.NP | ZELEZOBETONOVÁ KCE | Betonářské práce | 0 | 0 | @452@ | 1452Slo0000002883 | m3 | Sloup | EXISTING | yes | 0.6 | 0.6 | 0.36 | 1.206 | 1.206 | 3.35 | 8.04
 | Půdorys 1.NP | ZELEZOBETONOVÁ KCE | Betonářské práce | 0 | 0 | @452@ | 1452Slo0000002881 | m3 | Sloup | EXISTING | yes | 0.6 | 0.6 | 0.36 | 1.206 | 1.206 | 3.35 | 8.04
 | Půdorys 1.NP | ZELEZOBETONOVÁ KCE | Betonářské práce | 0 | 0 | @452@ | 1452Slo0000002829 | m3 | Sloup | EXISTING | yes | 0.4 | 0.4 | 0.16 | 0.536 | 0.536 | 3.35 | 5.36
 | Půdorys 1.NP | ZELEZOBETONOVÁ KCE | Betonářské práce | 0 | 0 | @452@ | 1452Slo0000002891 | m3 | Sloup | EXISTING | yes | 0.6 | 0.6 | 0.36 | 1.206 | 1.206 | 3.35 | 8.04
 | Půdorys 1.NP | ZELEZOBETONOVÁ KCE | Betonářské práce | 0 | 0 | @452@ | 1452Slo0000002841 | m3 | Sloup | EXISTING | yes | 0.4 | 0.4 | 0.16 | 0.536 | 0.536 | 3.35 | 5.36
 | Půdorys 1.NP | ZELEZOBETONOVÁ KCE | Betonářské práce | 0 | 0 | @452@ | 1452Slo0000002889 | m3 | Sloup | EXISTING | yes | 0.6 | 0.6 | 0.36 | 1.206 | 1.206 | 3.35 | 8.04
 | Půdorys 1.NP | ZELEZOBETONOVÁ KCE | Betonářské práce | 0 | 0 | @452@ | 1452Slo0000002835 | m3 | Sloup | EXISTING | yes | 0.4 | 0.4 | 0.16 | 0.536 | 0.536 | 3.35 | 5.36
 | Půdorys 1.NP | ZELEZOBETONOVÁ KCE | Betonářské práce | 0 | 0 | @452@ | 1452Slo0000002905 | m3 | Sloup | EXISTING | yes | 0.6 | 0.6 | 0.36 | 1.206 | 1.206 | 3.35 | 8.04
 | Půdorys 1.NP | ZELEZOBETONOVÁ KCE | Betonářské práce | 0 | 0 | @452@ | 1452Slo0000002901 | m3 | Sloup | EXISTING | yes | 0.6 | 0.6 | 0.36 | 1.206 | 1.206 | 3.35 | 8.04
 | Půdorys 1.NP | ZELEZOBETONOVÁ KCE | Betonářské práce | 0 | 0 | @452@ | 1452Slo0000002899 | m3 | Sloup | EXISTING | yes | 0.6 | 0.6 | 0.36 | 1.206 | 1.206 | 3.35 | 8.04
 | Půdorys 1.NP | ZELEZOBETONOVÁ KCE | Betonářské práce | 0 | 0 | @452@ | 1452Slo0000002839 | m3 | Sloup | EXISTING | yes | 0.4 | 0.4 | 0.16 | 0.536 | 0.536 | 3.35 | 5.36
 | Půdorys 1.NP | ZELEZOBETONOVÁ KCE | Betonářské práce | 0 | 0 | @452@ | 1452Slo0000002261 | m3 | Sloup | EXISTING | yes | 0.4 | 0.4 | 0.16 | 0.536 | 0.536 | 3.35 | 5.36
 | Půdorys 1.NP | ZELEZOBETONOVÁ KCE | Betonářské práce | 0 | 0 | @452@ | 1452Slo0000002260 | m3 | Sloup | EXISTING | yes | 0.4 | 0.4 | 0.16 | 0.536 | 0.536 | 3.35 | 5.36
 | Půdorys 1.NP | ZELEZOBETONOVÁ KCE | Betonářské práce | 0 | 0 | @452@ | 1452Slo0000002257 | m3 | Sloup | EXISTING | yes | 0.4 | 0.4 | 0.16 | 0.536 | 0.536 | 3.35 | 5.36
 | Půdorys 1.NP | ZELEZOBETONOVÁ KCE | Betonářské práce | 0 | 0 | @452@ | 1452Slo0000002258 | m3 | Sloup | EXISTING | yes | 0.4 | 0.4 | 0.16 | 0.536 | 0.536 | 3.35 | 5.36
 | Půdorys 1.NP | ZELEZOBETONOVÁ KCE | Betonářské práce | 0 | 0 | @452@ | 1452Slo0000002259 | m3 | Sloup | EXISTING | yes | 0.4 | 0.4 | 0.16 | 0.536 | 0.536 | 3.35 | 5.36
 | Půdorys 1.NP | ZELEZOBETONOVÁ KCE | Betonářské práce | 0 | 0 | @452@ | 1452Slo0000002907 | m3 | Sloup | EXISTING | yes | 0.6 | 0.6 | 0.36 | 1.206 | 1.206 | 3.35 | 8.04
 | Půdorys 1.NP | ZELEZOBETONOVÁ KCE | Betonářské práce | 0 | 0 | @452@ | 1452Slo0000002903 | m3 | Sloup | EXISTING | yes | 0.6 | 0.6 | 0.36 | 1.206 | 1.206 | 3.35 | 8.04
 | Půdorys 1.NP | ZELEZOBETONOVÁ KCE | Betonářské práce | 0 | 0 | @452@ | 1452Slo0000002895 | m3 | Sloup | EXISTING | yes | 0.6 | 0.6 | 0.36 | 1.206 | 1.206 | 3.35 | 8.04
 | Půdorys 1.NP | ZELEZOBETONOVÁ KCE | Betonářské práce | 0 | 0 | @452@ | 1452Slo0000002845 | m3 | Sloup | EXISTING | yes | 0.4 | 0.4 | 0.16 | 0.536 | 0.536 | 3.35 | 5.36
 | Půdorys 1.NP | ZELEZOBETONOVÁ KCE | Betonářské práce | 0 | 0 | @452@ | 1452Slo0000002251 | m3 | Sloup | EXISTING | yes | 0.4 | 0.4 | 0.16 | 0.536 | 0.536 | 3.35 | 5.36
 | Půdorys 1.NP | ZELEZOBETONOVÁ KCE | Betonářské práce | 0 | 0 | @452@ | 1452Slo0000002911 | m3 | Sloup | EXISTING | yes | 0.6 | 0.4 | 0.24 | 0.804 | 0.804 | 3.35 | 6.7
 | Půdorys 1.NP | ZELEZOBETONOVÁ KCE | Betonářské práce | 0 | 0 | @452@ | 1452Slo0000002887 | m3 | Sloup | EXISTING | yes | 0.6 | 0.6 | 0.36 | 1.206 | 1.206 | 3.35 | 8.04
 | Půdorys 1.NP | ZELEZOBETONOVÁ KCE | Betonářské práce | 0 | 0 | @452@ | 1452Slo0000002885 | m3 | Sloup | EXISTING | yes | 0.6 | 0.6 | 0.36 | 1.206 | 1.206 | 3.35 | 8.04
 | Půdorys 1.NP | ZELEZOBETONOVÁ KCE | Betonářské práce | 0 | 0 | @452@ | 1452Slo0000002833 | m3 | Sloup | EXISTING | yes | 0.4 | 0.4 | 0.16 | 0.536 | 0.536 | 3.35 | 5.36
 | Půdorys 1.NP | ZELEZOBETONOVÁ KCE | Betonářské práce | 0 | 0 | @452@ | 1452Slo0000002869 | m3 | Sloup | EXISTING | yes | 0.6 | 0.6 | 0.36 | 1.206 | 1.206 | 3.35 | 8.04
 | Půdorys 1.NP | ZELEZOBETONOVÁ KCE | Betonářské práce | 0 | 0 | @452@ | 1452Slo0000002853 | m3 | Sloup | EXISTING | yes | 0.6 | 0.6 | 0.36 | 1.206 | 1.206 | 3.35 | 8.04
 | Půdorys 1.NP | ZELEZOBETONOVÁ KCE | Betonářské práce | 0 | 0 | @452@ | 1452Slo0000002831 | m3 | Sloup | EXISTING | yes | 0.4 | 0.4 | 0.16 | 0.536 | 0.536 | 3.35 | 5.36
 | Půdorys 1.NP | ZELEZOBETONOVÁ KCE | Betonářské práce | 0 | 0 | @452@ | 1452Slo0000002861 | m3 | Sloup | EXISTING | yes | 0.6 | 0.6 | 0.36 | 1.206 | 1.206 | 3.35 | 8.04
 | Půdorys 1.NP | ZELEZOBETONOVÁ KCE | Betonářské práce |  |  |  | 1452Slo1096107425 | m3 | Sloup | EXISTING | yes | 0.4 | 0.4 | 0.16 | 0.536 | 0.536 | 3.35 | 5.36
 | Půdorys 1.NP | ZELEZOBETONOVÁ KCE | Betonářské práce |  |  |  | 1452Slo1096107430 | m3 | Sloup | EXISTING | yes | 0.4 | 0.4 | 0.16 | 0.536 | 0.536 | 3.35 | 5.36
 | Půdorys 1.NP | ZELEZOBETONOVÁ KCE | Betonářské práce |  |  |  | 1452Slo1096107471 | m3 | Sloup | EXISTING | yes | 0.4 | 0.4 | 0.16 | 0.536 | 0.536 | 3.35 | 5.36
 | Půdorys 1.NP | ZELEZOBETONOVÁ KCE | Betonářské práce | 0 | 0 | @452@ | 1452Slo0798421556 | m3 | Sloup | EXISTING | yes | 0.4 | 0.4 | 0.16 | 0.536 | 0.536 | 3.35 | 5.36
 | Půdorys 1.NP | ZELEZOBETONOVÁ KCE | Betonářské práce | 0 | 0 | @452@ | 1452Slo0798422595 | m3 | Sloup | EXISTING | yes | 0.4 | 0.4 | 0.16 | 0.536 | 0.536 | 3.35 | 5.36
 | Půdorys 1.NP | ZELEZOBETONOVÁ KCE | Betonářské práce | 0 | 0 | @452@ | 1452Slo0798422574 | m3 | Sloup | EXISTING | yes | 0.4 | 0.4 | 0.16 | 0.536 | 0.536 | 3.35 | 5.36
 | Půdorys 1.NP | ZELEZOBETONOVÁ KCE | Betonářské práce | 0 | 0 | @452@ | 1452Slo0798421319 | m3 | Sloup | EXISTING | yes | 0.4 | 0.4 | 0.16 | 0.536 | 0.536 | 3.35 | 5.36
 | Půdorys 1.NP | ZELEZOBETONOVÁ KCE | Betonářské práce | 0 | 0 | @452@ | 1452Slo0798421537 | m3 | Sloup | EXISTING | yes | 0.4 | 0.4 | 0.16 | 0.536 | 0.536 | 3.35 | 5.36
 | Půdorys 1.NP | ZELEZOBETONOVÁ KCE | Betonářské práce | 0 | 0 | @452@ | 1452Slo0798421322 | m3 | Sloup | EXISTING | yes | 0.4 | 0.4 | 0.16 | 0.536 | 0.536 | 3.35 | 5.36
 | Půdorys 1.NP | ZELEZOBETONOVÁ KCE | Betonářské práce | 0 | 0 | @452@ | 1452Slo0798421469 | m3 | Sloup | EXISTING | yes | 0.6 | 0.4 | 0.24 | 0.804 | 0.804 | 3.35 | 6.7
 | Půdorys 1.NP | ZELEZOBETONOVÁ KCE | Betonářské práce | 0 | 0 | @452@ | 1452Slo0000002849 | m3 | Sloup | EXISTING | yes | 0.6 | 0.6 | 0.36 | 1.206 | 1.206 | 3.35 | 8.04
 | Půdorys 1.NP | ZELEZOBETONOVÁ KCE | Betonářské práce | 0 | 0 | @452@ | 1452Slo0000002929 | m3 | Sloup | EXISTING | yes | 0.6 | 0.4 | 0.24 | 0.804 | 0.804 | 3.35 | 6.7
 | Půdorys 1.NP | ZELEZOBETONOVÁ KCE | Betonářské práce | 0 | 0 | @452@ | 1452Slo0000002893 | m3 | Sloup | EXISTING | yes | 0.6 | 0.6 | 0.36 | 1.206 | 1.206 | 3.35 | 8.04
 | Půdorys 1.NP | ZELEZOBETONOVÁ KCE | Betonářské práce | 0 | 0 | @452@ | 1452Slo0000002851 | m3 | Sloup | EXISTING | yes | 0.6 | 0.6 | 0.36 | 1.206 | 1.206 | 3.35 | 8.04
 | Půdorys 1.NP | ZELEZOBETONOVÁ KCE | Betonářské práce | 0 | 0 | @452@ | 1452Slo0000002865 | m3 | Sloup | EXISTING | yes | 0.6 | 0.6 | 0.36 | 1.206 | 1.206 | 3.35 | 8.04
 | Půdorys 1.NP | ZELEZOBETONOVÁ KCE | Betonářské práce | 0 | 0 | @452@ | 1452Slo0798416600 | m3 | Sloup | EXISTING | yes | 0.6 | 0.4 | 0.24 | 0.804 | 0.804 | 3.35 | 6.7
 | Půdorys 1.NP | ZELEZOBETONOVÁ KCE | Betonářské práce | 0 | 0 | @452@ | 1452Slo0000002931 | m3 | Sloup | EXISTING | yes | 0.6 | 0.4 | 0.24 | 0.804 | 0.804 | 3.35 | 6.7
 | Půdorys 1.NP | ZELEZOBETONOVÁ KCE | Betonářské práce | 0 | 0 | @452@ | 1452Slo0000002857 | m3 | Sloup | EXISTING | yes | 0.6 | 0.6 | 0.36 | 1.206 | 1.206 | 3.35 | 8.04
 | Půdorys 1.NP | ZELEZOBETONOVÁ KCE | Betonářské práce | 0 | 0 | @452@ | 1452Slo0000002855 | m3 | Sloup | EXISTING | yes | 0.6 | 0.6 | 0.36 | 1.206 | 1.206 | 3.35 | 8.04
 | Půdorys 1.NP | ZELEZOBETONOVÁ KCE | Betonářské práce | 0 | 0 | @452@ | 1452Slo0000002879 | m3 | Sloup | EXISTING | yes | 0.6 | 0.6 | 0.36 | 1.206 | 1.206 | 3.35 | 8.04
 | Půdorys 1.NP | ZELEZOBETONOVÁ KCE | Betonářské práce | 0 | 0 | @452@ | 1452Slo0000002873 | m3 | Sloup | EXISTING | yes | 0.6 | 0.6 | 0.36 | 1.206 | 1.206 | 3.35 | 8.04
 | Půdorys 1.NP | ZELEZOBETONOVÁ KCE | Betonářské práce | 0 | 0 | @452@ | 1452Slo0000002933 | m3 | Sloup | EXISTING | yes | 0.6 | 0.4 | 0.24 | 0.804 | 0.804 | 3.35 | 6.7
 | Půdorys 1.NP | ZELEZOBETONOVÁ KCE | Betonářské práce | 0 | 0 | @452@ | 1452Slo0000002925 | m3 | Sloup | EXISTING | yes | 0.6 | 0.4 | 0.24 | 0.804 | 0.804 | 3.35 | 6.7
 | Půdorys 1.NP | ZELEZOBETONOVÁ KCE | Betonářské práce | 0 | 0 | @452@ | 1452Slo0000002923 | m3 | Sloup | EXISTING | yes | 0.6 | 0.4 | 0.24 | 0.804 | 0.804 | 3.35 | 6.7
 | Půdorys 1.NP | ZELEZOBETONOVÁ KCE | Betonářské práce | 0 | 0 | @452@ | 1452Slo0000002921 | m3 | Sloup | EXISTING | yes | 0.6 | 0.4 | 0.24 | 0.804 | 0.804 | 3.35 | 6.7
 | Půdorys 1.NP | ZELEZOBETONOVÁ KCE | Betonářské práce | 0 | 0 | @452@ | 1452Slo0000002919 | m3 | Sloup | EXISTING | yes | 0.6 | 0.4 | 0.24 | 0.804 | 0.804 | 3.35 | 6.7
 | Půdorys 1.NP | ZELEZOBETONOVÁ KCE | Betonářské práce | 0 | 0 | @452@ | 1452Slo0000002859 | m3 | Sloup | EXISTING | yes | 0.6 | 0.6 | 0.36 | 1.206 | 1.206 | 3.35 | 8.04
 | Půdorys 1.NP | ZELEZOBETONOVÁ KCE | Betonářské práce | 0 | 0 | @452@ | 1452Slo0000002863 | m3 | Sloup | EXISTING | yes | 0.6 | 0.6 | 0.36 | 1.206 | 1.206 | 3.35 | 8.04
 | Půdorys 1.NP | ZELEZOBETONOVÁ KCE | Betonářské práce | 0 | 0 | @452@ | 1452Slo0000002871 | m3 | Sloup | EXISTING | yes | 0.6 | 0.6 | 0.36 | 1.206 | 1.206 | 3.35 | 8.04
 | Půdorys 1.NP | ZELEZOBETONOVÁ KCE | Betonářské práce | 0 | 0 | @452@ | 1452Slo0000002867 | m3 | Sloup | EXISTING | yes | 0.6 | 0.6 | 0.36 | 1.206 | 1.206 | 3.35 | 8.04
OCHRANNÝ SLOUPEK | Půdorys 1.NP | I.OS4 | Zámečnické práce |  |  |  | 1464Slo1096238666 | Kus | OCHRANNÝ SLOUPEK |  |  | 0 | 0 | 0.005 | 0.004 | 0.004 | 0.9 | 0.214 | NEMSOK - Kód prvku: OV00.03.4001; Označení: OCHRANNÝ SLOUPEK
OCHRANNÝ SLOUPEK | Půdorys 1.NP | I.OS4 | Zámečnické práce |  |  |  | 1464Slo1096238690 | Kus | OCHRANNÝ SLOUPEK |  |  | 0 | 0 | 0.005 | 0.004 | 0.004 | 0.9 | 0.214 | NEMSOK - Kód prvku: OV00.03.4001; Označení: OCHRANNÝ SLOUPEK
OCHRANNÝ SLOUPEK | Půdorys 1.NP | I.OS4 | Zámečnické práce |  |  |  | 1464Slo1096238694 | Kus | OCHRANNÝ SLOUPEK |  |  | 0 | 0 | 0.005 | 0.004 | 0.004 | 0.9 | 0.214 | NEMSOK - Kód prvku: OV00.03.4001; Označení: OCHRANNÝ SLOUPEK
OCHRANNÝ SLOUPEK | Půdorys 1.NP | I.OS4 | Zámečnické práce |  |  |  | 1464Slo1096238696 | Kus | OCHRANNÝ SLOUPEK |  |  | 0 | 0 | 0.005 | 0.004 | 0.004 | 0.9 | 0.214 | NEMSOK - Kód prvku: OV00.03.4001; Označení: OCHRANNÝ SLOUPEK
OCHRANNÝ SLOUPEK | Půdorys 1.NP | I.OS4 | Zámečnické práce |  |  |  | 1464Slo1096238706 | Kus | OCHRANNÝ SLOUPEK |  |  | 0 | 0 | 0.005 | 0.004 | 0.004 | 0.9 | 0.214 | NEMSOK - Kód prvku: OV00.03.4001; Označení: OCHRANNÝ SLOUPEK
OCHRANNÝ SLOUPEK | Půdorys 1.NP | I.OS4 | Zámečnické práce |  |  |  | 1464Slo1096238708 | Kus | OCHRANNÝ SLOUPEK |  |  | 0 | 0 | 0.005 | 0.004 | 0.004 | 0.9 | 0.214 | NEMSOK - Kód prvku: OV00.03.4001; Označení: OCHRANNÝ SLOUPEK
OCHRANNÝ SLOUPEK | Půdorys 1.NP | I.OS4 | Zámečnické práce |  |  |  | 1464Slo1096238710 | Kus | OCHRANNÝ SLOUPEK |  |  | 0 | 0 | 0.005 | 0.004 | 0.004 | 0.9 | 0.214 | NEMSOK - Kód prvku: OV00.03.4001; Označení: OCHRANNÝ SLOUPEK
OCHRANNÝ SLOUPEK | Půdorys 1.NP | I.OS4 | Zámečnické práce |  |  |  | 1464Slo1096238712 | Kus | OCHRANNÝ SLOUPEK |  |  | 0 | 0 | 0.005 | 0.004 | 0.004 | 0.9 | 0.214 | NEMSOK - Kód prvku: OV00.03.4001; Označení: OCHRANNÝ SLOUPEK
OCHRANNÝ SLOUPEK | Půdorys 1.NP | I.OS4 | Zámečnické práce |  |  |  | 1464Slo1096238714 | Kus | OCHRANNÝ SLOUPEK |  |  | 0 | 0 | 0.005 | 0.004 | 0.004 | 0.9 | 0.214 | NEMSOK - Kód prvku: OV00.03.4001; Označení: OCHRANNÝ SLOUPEK
OCHRANNÝ SLOUPEK | Půdorys 1.NP | I.OS4 | Zámečnické práce |  |  |  | 1464Slo1096238716 | Kus | OCHRANNÝ SLOUPEK |  |  | 0 | 0 | 0.005 | 0.004 | 0.004 | 0.9 | 0.214 | NEMSOK - Kód prvku: OV00.03.4001; Označení: OCHRANNÝ SLOUPEK
OCHRANNÝ SLOUPEK | Půdorys 1.NP | I.OS4 | Zámečnické práce |  |  |  | 1464Slo1096238718 | Kus | OCHRANNÝ SLOUPEK |  |  | 0 | 0 | 0.005 | 0.004 | 0.004 | 0.9 | 0.214 | NEMSOK - Kód prvku: OV00.03.4001; Označení: OCHRANNÝ SLOUPEK
OCHRANNÝ SLOUPEK | Půdorys 1.NP | I.OS4 | Zámečnické práce |  |  |  | 1464Slo1096238720 | Kus | OCHRANNÝ SLOUPEK |  |  | 0 | 0 | 0.005 | 0.004 | 0.004 | 0.9 | 0.214 | NEMSOK - Kód prvku: OV00.03.4001; Označení: OCHRANNÝ SLOUPEK
OCHRANNÝ SLOUPEK | Půdorys 1.NP | I.OS4 | Zámečnické práce |  |  |  | 1464Slo1096238722 | Kus | OCHRANNÝ SLOUPEK |  |  | 0 | 0 | 0.005 | 0.004 | 0.004 | 0.9 | 0.214 | NEMSOK - Kód prvku: OV00.03.4001; Označení: OCHRANNÝ SLOUPEK
OCHRANNÝ SLOUPEK | Půdorys 1.NP | I.OS4 | Zámečnické práce |  |  |  | 1464Slo1096238724 | Kus | OCHRANNÝ SLOUPEK |  |  | 0 | 0 | 0.005 | 0.004 | 0.004 | 0.9 | 0.214 | NEMSOK - Kód prvku: OV00.03.4001; Označení: OCHRANNÝ SLOUPEK
OCHRANNÝ SLOUPEK | Půdorys 1.NP | I.OS4 | Zámečnické práce |  |  |  | 1464Slo1096238726 | Kus | OCHRANNÝ SLOUPEK |  |  | 0 | 0 | 0.005 | 0.004 | 0.004 | 0.9 | 0.214 | NEMSOK - Kód prvku: OV00.03.4001; Označení: OCHRANNÝ SLOUPEK
OCHRANNÝ SLOUPEK | Půdorys 1.NP | I.OS4 | Zámečnické práce |  |  |  | 1464Slo1096238728 | Kus | OCHRANNÝ SLOUPEK |  |  | 0 | 0 | 0.005 | 0.004 | 0.004 | 0.9 | 0.214 | NEMSOK - Kód prvku: OV00.03.4001; Označení: OCHRANNÝ SLOUPEK
OCHRANNÝ SLOUPEK | Půdorys 1.NP | I.OS4 | Zámečnické práce |  |  |  | 1464Slo1096238730 | Kus | OCHRANNÝ SLOUPEK |  |  | 0 | 0 | 0.005 | 0.004 | 0.004 | 0.9 | 0.214 | NEMSOK - Kód prvku: OV00.03.4001; Označení: OCHRANNÝ SLOUPEK
OCHRANNÝ SLOUPEK | Půdorys 1.NP | I.OS4 | Zámečnické práce |  |  |  | 1464Slo1096238782 | Kus | OCHRANNÝ SLOUPEK |  |  | 0 | 0 | 0.005 | 0.004 | 0.004 | 0.9 | 0.214 | NEMSOK - Kód prvku: OV00.03.4001; Označení: OCHRANNÝ SLOUPEK
OCHRANNÝ SLOUPEK | Půdorys 1.NP | I.OS4 | Zámečnické práce |  |  |  | 1464Slo1096238831 | Kus | OCHRANNÝ SLOUPEK |  |  | 0 | 0 | 0.005 | 0.004 | 0.004 | 0.9 | 0.214 | NEMSOK - Kód prvku: OV00.03.4001; Označení: OCHRANNÝ SLOUPEK
OCHRANNÝ SLOUPEK | Půdorys 1.NP | I.OS4 | Zámečnické práce |  |  |  | 1464Slo1096238832 | Kus | OCHRANNÝ SLOUPEK |  |  | 0 | 0 | 0.005 | 0.004 | 0.004 | 0.9 | 0.214 | NEMSOK - Kód prvku: OV00.03.4001; Označení: OCHRANNÝ SLOUPEK
OCHRANNÝ SLOUPEK | Půdorys 1.NP | I.OS4 | Zámečnické práce |  |  |  | 1464Slo1096238835 | Kus | OCHRANNÝ SLOUPEK |  |  | 0 | 0 | 0.005 | 0.004 | 0.004 | 0.9 | 0.214 | NEMSOK - Kód prvku: OV00.03.4001; Označení: OCHRANNÝ SLOUPEK
OCHRANNÝ SLOUPEK | Půdorys 1.NP | I.OS4 | Zámečnické práce |  |  |  | 1464Slo1096238836 | Kus | OCHRANNÝ SLOUPEK |  |  | 0 | 0 | 0.005 | 0.004 | 0.004 | 0.9 | 0.214 | NEMSOK - Kód prvku: OV00.03.4001; Označení: OCHRANNÝ SLOUPEK
OCHRANNÝ SLOUPEK | Půdorys 1.NP | I.OS4 | Zámečnické práce |  |  |  | 1464Slo1096238837 | Kus | OCHRANNÝ SLOUPEK |  |  | 0 | 0 | 0.005 | 0.004 | 0.004 | 0.9 | 0.214 | NEMSOK - Kód prvku: OV00.03.4001; Označení: OCHRANNÝ SLOUPEK
OCHRANNÝ SLOUPEK | Půdorys 1.NP | I.OS4 | Zámečnické práce |  |  |  | 1464Slo1096238838 | Kus | OCHRANNÝ SLOUPEK |  |  | 0 | 0 | 0.005 | 0.004 | 0.004 | 0.9 | 0.214 | NEMSOK - Kód prvku: OV00.03.4001; Označení: OCHRANNÝ SLOUPEK
OCHRANNÝ SLOUPEK | Půdorys 1.NP | I.OS4 | Zámečnické práce |  |  |  | 1464Slo1096238839 | Kus | OCHRANNÝ SLOUPEK |  |  | 0 | 0 | 0.005 | 0.004 | 0.004 | 0.9 | 0.214 | NEMSOK - Kód prvku: OV00.03.4001; Označení: OCHRANNÝ SLOUPEK
OCHRANNÝ SLOUPEK | Půdorys 1.NP | I.OS4 | Zámečnické práce |  |  |  | 1464Slo1096238840 | Kus | OCHRANNÝ SLOUPEK |  |  | 0 | 0 | 0.005 | 0.004 | 0.004 | 0.9 | 0.214 | NEMSOK - Kód prvku: OV00.03.4001; Označení: OCHRANNÝ SLOUPEK
OCHRANNÝ SLOUPEK | Půdorys 1.NP | I.OS4 | Zámečnické práce |  |  |  | 1464Slo1096238841 | Kus | OCHRANNÝ SLOUPEK |  |  | 0 | 0 | 0.005 | 0.004 | 0.004 | 0.9 | 0.214 | NEMSOK - Kód prvku: OV00.03.4001; Označení: OCHRANNÝ SLOUPEK
OCHRANNÝ SLOUPEK | Půdorys 1.NP | I.OS4 | Zámečnické práce |  |  |  | 1464Slo1096238842 | Kus | OCHRANNÝ SLOUPEK |  |  | 0 | 0 | 0.005 | 0.004 | 0.004 | 0.9 | 0.214 | NEMSOK - Kód prvku: OV00.03.4001; Označení: OCHRANNÝ SLOUPEK
OCHRANNÝ SLOUPEK | Půdorys 1.NP | I.OS4 | Zámečnické práce |  |  |  | 1464Slo1096238843 | Kus | OCHRANNÝ SLOUPEK |  |  | 0 | 0 | 0.005 | 0.004 | 0.004 | 0.9 | 0.214 | NEMSOK - Kód prvku: OV00.03.4001; Označení: OCHRANNÝ SLOUPEK
OCHRANNÝ SLOUPEK | Půdorys 1.NP | I.OS4 | Zámečnické práce |  |  |  | 1464Slo1096238844 | Kus | OCHRANNÝ SLOUPEK |  |  | 0 | 0 | 0.005 | 0.004 | 0.004 | 0.9 | 0.214 | NEMSOK - Kód prvku: OV00.03.4001; Označení: OCHRANNÝ SLOUPEK
OCHRANNÝ SLOUPEK | Půdorys 1.NP | I.OS4 | Zámečnické práce |  |  |  | 1464Slo1096238845 | Kus | OCHRANNÝ SLOUPEK |  |  | 0 | 0 | 0.005 | 0.004 | 0.004 | 0.9 | 0.214 | NEMSOK - Kód prvku: OV00.03.4001; Označení: OCHRANNÝ SLOUPEK
OCHRANNÝ SLOUPEK | Půdorys 1.NP | I.OS4 | Zámečnické práce |  |  |  | 1464Slo1096238846 | Kus | OCHRANNÝ SLOUPEK |  |  | 0 | 0 | 0.005 | 0.004 | 0.004 | 0.9 | 0.214 | NEMSOK - Kód prvku: OV00.03.4001; Označení: OCHRANNÝ SLOUPEK
OCHRANNÝ SLOUPEK | Půdorys 1.NP | I.OS4 | Zámečnické práce |  |  |  | 1464Slo1096238847 | Kus | OCHRANNÝ SLOUPEK |  |  | 0 | 0 | 0.005 | 0.004 | 0.004 | 0.9 | 0.214 | NEMSOK - Kód prvku: OV00.03.4001; Označení: OCHRANNÝ SLOUPEK
OCHRANNÝ SLOUPEK | Půdorys 1.NP | I.OS4 | Zámečnické práce |  |  |  | 1464Slo1096238848 | Kus | OCHRANNÝ SLOUPEK |  |  | 0 | 0 | 0.005 | 0.004 | 0.004 | 0.9 | 0.214 | NEMSOK - Kód prvku: OV00.03.4001; Označení: OCHRANNÝ SLOUPEK
OCHRANNÝ SLOUPEK | Půdorys 1.NP | I.OS4 | Zámečnické práce |  |  |  | 1464Slo1096238849 | Kus | OCHRANNÝ SLOUPEK |  |  | 0 | 0 | 0.005 | 0.004 | 0.004 | 0.9 | 0.214 | NEMSOK - Kód prvku: OV00.03.4001; Označení: OCHRANNÝ SLOUPEK
OCHRANNÝ SLOUPEK | Půdorys 1.NP | I.OS4 | Zámečnické práce |  |  |  | 1464Slo1096238850 | Kus | OCHRANNÝ SLOUPEK |  |  | 0 | 0 | 0.005 | 0.004 | 0.004 | 0.9 | 0.214 | NEMSOK - Kód prvku: OV00.03.4001; Označení: OCHRANNÝ SLOUPEK
OCHRANNÝ SLOUPEK | Půdorys 1.NP | I.OS4 | Zámečnické práce |  |  |  | 1464Slo1096238851 | Kus | OCHRANNÝ SLOUPEK |  |  | 0 | 0 | 0.005 | 0.004 | 0.004 | 0.9 | 0.214 | NEMSOK - Kód prvku: OV00.03.4001; Označení: OCHRANNÝ SLOUPEK
OCHRANNÝ SLOUPEK | Půdorys 1.NP | I.OS4 | Zámečnické práce |  |  |  | 1464Slo1096238852 | Kus | OCHRANNÝ SLOUPEK |  |  | 0 | 0 | 0.005 | 0.004 | 0.004 | 0.9 | 0.214 | NEMSOK - Kód prvku: OV00.03.4001; Označení: OCHRANNÝ SLOUPEK
OCHRANNÝ SLOUPEK | Půdorys 1.NP | I.OS4 | Zámečnické práce |  |  |  | 1464Slo1096238853 | Kus | OCHRANNÝ SLOUPEK |  |  | 0 | 0 | 0.005 | 0.004 | 0.004 | 0.9 | 0.214 | NEMSOK - Kód prvku: OV00.03.4001; Označení: OCHRANNÝ SLOUPEK
OCHRANNÝ SLOUPEK | Půdorys 1.NP | I.OS4 | Zámečnické práce |  |  |  | 1464Slo1096238854 | Kus | OCHRANNÝ SLOUPEK |  |  | 0 | 0 | 0.005 | 0.004 | 0.004 | 0.9 | 0.214 | NEMSOK - Kód prvku: OV00.03.4001; Označení: OCHRANNÝ SLOUPEK
OCHRANNÝ SLOUPEK | Půdorys 1.NP | I.OS4 | Zámečnické práce |  |  |  | 1464Slo1096242861 | Kus | OCHRANNÝ SLOUPEK |  |  | 0 | 0 | 0.005 | 0.004 | 0.004 | 0.9 | 0.214 | NEMSOK - Kód prvku: OV00.03.4001; Označení: OCHRANNÝ SLOUPEK
OCHRANNÝ SLOUPEK | Půdorys 1.NP | I.OS4 | Zámečnické práce |  |  |  | 1464Slo1096242862 | Kus | OCHRANNÝ SLOUPEK |  |  | 0 | 0 | 0.005 | 0.004 | 0.004 | 0.9 | 0.214 | NEMSOK - Kód prvku: OV00.03.4001; Označení: OCHRANNÝ SLOUPEK
OCHRANNÝ SLOUPEK | Půdorys 1.NP | I.OS4 | Zámečnické práce |  |  |  | 1464Slo1096242911 | Kus | OCHRANNÝ SLOUPEK |  |  | 0 | 0 | 0.005 | 0.004 | 0.004 | 0.9 | 0.214 | NEMSOK - Kód prvku: OV00.03.4001; Označení: OCHRANNÝ SLOUPEK
OCHRANNÝ SLOUPEK | Půdorys 1.NP | I.OS4 | Zámečnické práce |  |  |  | 1464Slo1096242912 | Kus | OCHRANNÝ SLOUPEK |  |  | 0 | 0 | 0.005 | 0.004 | 0.004 | 0.9 | 0.214 | NEMSOK - Kód prvku: OV00.03.4001; Označení: OCHRANNÝ SLOUPEK
OCHRANNÝ SLOUPEK | Půdorys 1.NP | I.OS4 | Zámečnické práce |  |  |  | 1464Slo1096246938 | Kus | OCHRANNÝ SLOUPEK |  |  | 0 | 0 | 0.005 | 0.004 | 0.004 | 0.9 | 0.214 | NEMSOK - Kód prvku: OV00.03.4001; Označení: OCHRANNÝ SLOUPEK
OCHRANNÝ SLOUPEK | Půdorys 1.NP | I.OS4 | Zámečnické práce |  |  |  | 1464Slo1096248956 | Kus | OCHRANNÝ SLOUPEK |  |  | 0 | 0 | 0.005 | 0.004 | 0.004 | 0.9 | 0.214 | NEMSOK - Kód prvku: OV00.03.4001; Označení: OCHRANNÝ SLOUPEK
OCHRANNÝ SLOUPEK | Půdorys 1.NP | I.OS4 | Zámečnické práce |  |  |  | 1464Slo1096248957 | Kus | OCHRANNÝ SLOUPEK |  |  | 0 | 0 | 0.005 | 0.004 | 0.004 | 0.9 | 0.214 | NEMSOK - Kód prvku: OV00.03.4001; Označení: OCHRANNÝ SLOUPEK
OCHRANNÝ SLOUPEK | Půdorys 1.NP | I.OS4 | Zámečnické práce |  |  |  | 1464Slo1096248950 | Kus | OCHRANNÝ SLOUPEK |  |  | 0 | 0 | 0.005 | 0.004 | 0.004 | 0.9 | 0.214 | NEMSOK - Kód prvku: OV00.03.4001; Označení: OCHRANNÝ SLOUPEK
OCHRANNÝ SLOUPEK | Půdorys 1.NP | I.OS4 | Zámečnické práce |  |  |  | 1464Slo1096238781 | Kus | OCHRANNÝ SLOUPEK |  |  | 0 | 0 | 0.005 | 0.004 | 0.004 | 0.9 | 0.214 | NEMSOK - Kód prvku: OV00.03.4001; Označení: OCHRANNÝ SLOUPEK
OCHRANNÝ SLOUPEK | Půdorys 1.NP | I.OS4 | Zámečnické práce |  |  |  | 1464Slo1096248953 | Kus | OCHRANNÝ SLOUPEK |  |  | 0 | 0 | 0.005 | 0.004 | 0.004 | 0.9 | 0.214 | NEMSOK - Kód prvku: OV00.03.4001; Označení: OCHRANNÝ SLOUPEK
OCHRANNÝ SLOUPEK | Půdorys 1.NP | I.OS4 | Zámečnické práce |  |  |  | 1464Slo1096244927 | Kus | OCHRANNÝ SLOUPEK |  |  | 0 | 0 | 0.005 | 0.004 | 0.004 | 0.9 | 0.214 | NEMSOK - Kód prvku: OV00.03.4001; Označení: OCHRANNÝ SLOUPEK
OCHRANNÝ SLOUPEK | Půdorys 1.NP | I.OS4 | Zámečnické práce |  |  |  | 1464Slo1096238752 | Kus | OCHRANNÝ SLOUPEK |  |  | 0 | 0 | 0.005 | 0.004 | 0 | 0.9 | 0.448 | NEMSOK - Kód prvku: OV00.03.4001; Označení: OCHRANNÝ SLOUPEK
OCHRANNÝ SLOUPEK | Půdorys 1.NP | I.OS4 | Zámečnické práce |  |  |  | 1464Slo1096238731 | Kus | OCHRANNÝ SLOUPEK |  |  | 0 | 0 | 0.005 | 0.004 | 0 | 0.9 | 0.448 | NEMSOK - Kód prvku: OV00.03.4001; Označení: OCHRANNÝ SLOUPEK
OCHRANNÝ SLOUPEK | Půdorys 1.NP | I.OS4 | Zámečnické práce |  |  |  | 1464Slo1096244920 | Kus | OCHRANNÝ SLOUPEK |  |  | 0 | 0 | 0.005 | 0.004 | 0.004 | 0.9 | 0.214 | NEMSOK - Kód prvku: OV00.03.4001; Označení: OCHRANNÝ SLOUPEK
 | Půdorys 1.NP | ZELEZOBETONOVÁ KCE | Betonářské práce | 200 |  |  | 1464Slo1096156942 | m3 | Sloup | NEW | yes | 0 | 0 | 0.159 | 0.565 | 0.565 | 3.55 | 5.025 | NEMSOK - Kód prvku: SL02.03.0004; Třída pevnosti ocele: B500B; Podlaží: 1.NP; Požární odolnost: R 45DP1; Třída pevnosti betonu: C25/30-XC1; Krytí výztuže: 35mm; Funkce (venkovní): Ne; Statická funkce: Ano
 | Půdorys 1.NP | ZELEZOBETONOVÁ KCE | Betonářské práce | 200 |  |  | 1464Slo1096156944 | m3 | Sloup | NEW | yes | 0 | 0 | 0.159 | 0.588 | 0.588 | 3.7 | 5.237 | NEMSOK - Kód prvku: SL02.03.0005; Třída pevnosti ocele: B500B; Podlaží: 1.NP; Požární odolnost: R 45DP1; Třída pevnosti betonu: C25/30-XC1; Krytí výztuže: 35mm; Funkce (venkovní): Ne; Statická funkce: Ano
 | Půdorys 1.NP | ZELEZOBETONOVÁ KCE | Betonářské práce | 200 |  |  | 1464Slo1096159375 | m3 | Sloup | NEW | yes | 0.5 | 0.25 | 0.125 | 0.463 | 0.463 | 3.7 | 5.55 | NEMSOK - Kód prvku: SL02.03.0006; Třída pevnosti ocele: B500B; Podlaží: 1.NP; Požární odolnost: R 45DP1; Třída pevnosti betonu: C25/30-XC1; Krytí výztuže: 35mm; Funkce (venkovní): Ne; Statická funkce: Ano
 | Půdorys 1.NP | ZELEZOBETONOVÁ KCE | Betonářské práce | 200 |  |  | 1464Slo1096159369 | m3 | Sloup | NEW | yes | 0.5 | 0.25 | 0.125 | 0.444 | 0.444 | 3.55 | 5.325 | NEMSOK - Kód prvku: SL02.03.0007; Třída pevnosti ocele: B500B; Podlaží: 1.NP; Požární odolnost: R 45DP1; Třída pevnosti betonu: C25/30-XC1; Krytí výztuže: 35mm; Funkce (venkovní): Ne; Statická funkce: Ano
 | Půdorys 1.NP | ZELEZOBETONOVÁ KCE | Betonářské práce | 200 |  |  | 1464Slo1096163811 | m3 | Sloup | NEW | yes | 0.5 | 0.25 | 0.125 | 0.462 | 0.462 | 3.7 | 5.55 | NEMSOK - Kód prvku: SL02.03.0008; Třída pevnosti ocele: B500B; Podlaží: 1.NP; Požární odolnost: R 45DP1; Třída pevnosti betonu: C25/30-XC1; Krytí výztuže: 35mm; Funkce (venkovní): Ne; Statická funkce: Ano
 | Půdorys 1.NP | ZELEZOBETONOVÁ KCE | Betonářské práce | 150 |  |  | 1464Slo1096286937 | m3 | Sloup | NEW | yes | 0.2 | 0.5 | 0.1 | 0.355 | 0.355 | 3.55 | 4.97 | NEMSOK - Kód prvku: SL02.03.0009; Třída pevnosti ocele: B500B; Podlaží: 1.NP; Požární odolnost: R 30DP1; Třída pevnosti betonu: C25/30-XC1; Krytí výztuže: 35mm; Funkce (venkovní): Ne; Statická funkce: Ano
 | Půdorys 1.NP | ZELEZOBETONOVÁ KCE | Betonářské práce | 200 |  |  | 1464Slo1096157555 | m3 | Sloup | NEW | yes | 0.4 | 0.4 | 0.16 | 0.568 | 0.568 | 3.55 | 5.68 | NEMSOK - Kód prvku: SL02.03.0003; Třída pevnosti ocele: B500B; Podlaží: 1.NP; Požární odolnost: R 45DP1; Třída pevnosti betonu: C25/30-XC1; Krytí výztuže: 35mm; Funkce (venkovní): Ne; Statická funkce: Ano
 | Půdorys 1.NP | PROSKLENÁ FASÁDA - SLOUPEK | Zavěšené fasády |  |  |  | 1464Slo1096158517 | m3 | Sloup | NEW | no | 0.05 | 0.22 | 0.011 | 0.041 | 0.041 | 3.7 | 1.998 | NEMSOK - Kód prvku: LP01.02.0001; Požární odolnost: bez požadavku; Funkce (venkovní): Ano; Neprůzvučnost: 37 dB; Pset_ColumnCommon - ThermalTransmittance: 0.7 W/K/m2
 | Půdorys 1.NP | PROSKLENÁ FASÁDA - SLOUPEK | Zavěšené fasády |  |  |  | 1464Slo1096158519 | m3 | Sloup | NEW | no | 0.05 | 0.22 | 0.011 | 0.041 | 0.041 | 3.7 | 1.998 | NEMSOK - Kód prvku: LP01.02.0001; Požární odolnost: bez požadavku; Funkce (venkovní): Ano; Neprůzvučnost: 37 dB; Pset_ColumnCommon - ThermalTransmittance: 0.7 W/K/m2
 | Půdorys 1.NP | PROSKLENÁ FASÁDA - SLOUPEK | Zavěšené fasády |  |  |  | 1464Slo1096158525 | m3 | Sloup | NEW | no | 0.05 | 0.22 | 0.011 | 0.041 | 0.041 | 3.7 | 1.998 | NEMSOK - Kód prvku: LP01.02.0001; Požární odolnost: bez požadavku; Funkce (venkovní): Ano; Neprůzvučnost: 37 dB; Pset_ColumnCommon - ThermalTransmittance: 0.7 W/K/m2
 | Půdorys 1.NP | PROSKLENÁ FASÁDA - SLOUPEK | Zavěšené fasády |  |  |  | 1464Slo1096158527 | m3 | Sloup | NEW | no | 0.05 | 0.22 | 0.011 | 0.041 | 0.041 | 3.7 | 1.998 | NEMSOK - Kód prvku: LP01.02.0001; Požární odolnost: bez požadavku; Funkce (venkovní): Ano; Neprůzvučnost: 37 dB; Pset_ColumnCommon - ThermalTransmittance: 0.7 W/K/m2
 | Půdorys 1.NP | PROSKLENÁ FASÁDA - SLOUPEK | Zavěšené fasády |  |  |  | 1464Slo1096158529 | m3 | Sloup | NEW | no | 0.05 | 0.22 | 0.011 | 0.041 | 0.041 | 3.7 | 1.998 | NEMSOK - Kód prvku: LP01.02.0001; Požární odolnost: bez požadavku; Funkce (venkovní): Ano; Neprůzvučnost: 37 dB; Pset_ColumnCommon - ThermalTransmittance: 0.7 W/K/m2
 | Půdorys 1.NP | PROSKLENÁ FASÁDA - SLOUPEK | Zavěšené fasády |  |  |  | 1464Slo1096159359 | m3 | Sloup | NEW | no | 0.05 | 0.22 | 0.011 | 0.041 | 0.041 | 3.7 | 1.998 | NEMSOK - Kód prvku: LP01.02.0001; Požární odolnost: bez požadavku; Funkce (venkovní): Ano; Neprůzvučnost: 37 dB; Pset_ColumnCommon - ThermalTransmittance: 0.7 W/K/m2
 | Půdorys 1.NP | PROSKLENÁ FASÁDA - SLOUPEK | Zavěšené fasády |  |  |  | 1464Slo1096158515 | m3 | Sloup | NEW | no | 0.05 | 0.22 | 0.011 | 0.041 | 0.041 | 3.7 | 1.998 | NEMSOK - Kód prvku: LP01.02.0001; Požární odolnost: bez požadavku; Funkce (venkovní): Ano; Neprůzvučnost: 37 dB; Pset_ColumnCommon - ThermalTransmittance: 0.7 W/K/m2
 | Půdorys 1.NP | ZELEZOBETONOVÁ KCE | Betonářské práce | 200 |  |  | 1464Slo1096159280 | m3 | Sloup | NEW | yes | 1 | 0.45 | 0.415 | 1.619 | 1.619 | 3.9 | 9.963 | NEMSOK - Kód prvku: SL02.03.0002; Třída pevnosti ocele: B500B; Podlaží: 1.NP; Požární odolnost: bez požadavku; Třída pevnosti betonu: C25/30-XC4; Krytí výztuže: 35mm; Funkce (venkovní): Ano; Statická funkce: Ano
 | Půdorys 1.NP | ZELEZOBETONOVÁ KCE | Betonářské práce | 200 |  |  | 1464Slo1096159270 | m3 | Sloup | NEW | yes | 0 | 0 | 0.159 | 0.62 | 0.62 | 3.9 | 5.521 | NEMSOK - Kód prvku: SL02.03.0001; Třída pevnosti ocele: B500B; Podlaží: 1.NP; Požární odolnost: bez požadavku; Třída pevnosti betonu: C25/30-XC4; Krytí výztuže: 35mm; Funkce (venkovní): Ano; Statická funkce: Ano
 | Půdorys 2.NP | ZELEZOBETONOVÁ KCE | Betonářské práce | 0 | 0 | @452@ | 1552Slo0000001792 | m3 | Sloup | EXISTING | yes | 0.4 | 0.4 | 0.16 | 0.536 | 0.536 | 3.35 | 5.36
 | Půdorys 2.NP | ZELEZOBETONOVÁ KCE | Betonářské práce | 0 | 0 | @452@ | 1552Slo0798422395 | m3 | Sloup | EXISTING | yes | 0.6 | 0.6 | 0.36 | 1.206 | 1.206 | 3.35 | 8.04
 | Půdorys 2.NP | ZELEZOBETONOVÁ KCE | Betonářské práce | 0 | 0 | @452@ | 1552Slo0798420331 | m3 | Sloup | EXISTING | yes | 0.6 | 0.6 | 0.36 | 1.206 | 1.206 | 3.35 | 8.04
 | Půdorys 2.NP | ZELEZOBETONOVÁ KCE | Betonářské práce | 0 | 0 | @452@ | 1552Slo0798420329 | m3 | Sloup | EXISTING | yes | 0.6 | 0.6 | 0.36 | 1.206 | 1.206 | 3.35 | 8.04
 | Půdorys 2.NP | ZELEZOBETONOVÁ KCE | Betonářské práce | 0 | 0 | @452@ | 1552Slo0798420327 | m3 | Sloup | EXISTING | yes | 0.6 | 0.6 | 0.36 | 1.206 | 1.206 | 3.35 | 8.04
 | Půdorys 2.NP | ZELEZOBETONOVÁ KCE | Betonářské práce | 0 | 0 | @452@ | 1552Slo0798420325 | m3 | Sloup | EXISTING | yes | 0.6 | 0.6 | 0.36 | 1.206 | 1.206 | 3.35 | 8.04
 | Půdorys 2.NP | ZELEZOBETONOVÁ KCE | Betonářské práce | 0 | 0 | @452@ | 1552Slo0798420323 | m3 | Sloup | EXISTING | yes | 0.6 | 0.6 | 0.36 | 1.206 | 1.206 | 3.35 | 8.04
 | Půdorys 2.NP | ZELEZOBETONOVÁ KCE | Betonářské práce | 0 | 0 | @452@ | 1552Slo0798420321 | m3 | Sloup | EXISTING | yes | 0.6 | 0.6 | 0.36 | 1.206 | 1.206 | 3.35 | 8.04
 | Půdorys 2.NP | ZELEZOBETONOVÁ KCE | Betonářské práce | 0 | 0 | @452@ | 1552Slo0798420319 | m3 | Sloup | EXISTING | yes | 0.6 | 0.6 | 0.36 | 1.206 | 1.206 | 3.35 | 8.04
 | Půdorys 2.NP | ZELEZOBETONOVÁ KCE | Betonářské práce | 0 | 0 | @452@ | 1552Slo0798420317 | m3 | Sloup | EXISTING | yes | 0.6 | 0.6 | 0.36 | 1.206 | 1.206 | 3.35 | 8.04
 | Půdorys 2.NP | ZELEZOBETONOVÁ KCE | Betonářské práce | 0 | 0 | @452@ | 1552Slo0798420315 | m3 | Sloup | EXISTING | yes | 0.6 | 0.6 | 0.36 | 1.206 | 1.206 | 3.35 | 8.04
 | Půdorys 2.NP | ZELEZOBETONOVÁ KCE | Betonářské práce | 0 | 0 | @452@ | 1552Slo0798420313 | m3 | Sloup | EXISTING | yes | 0.6 | 0.6 | 0.36 | 1.206 | 1.206 | 3.35 | 8.04
 | Půdorys 2.NP | ZELEZOBETONOVÁ KCE | Betonářské práce | 0 | 0 | @452@ | 1552Slo0798420311 | m3 | Sloup | EXISTING | yes | 0.6 | 0.6 | 0.36 | 1.206 | 1.206 | 3.35 | 8.04
 | Půdorys 2.NP | ZELEZOBETONOVÁ KCE | Betonářské práce | 0 | 0 | @452@ | 1552Slo0798420309 | m3 | Sloup | EXISTING | yes | 0.6 | 0.6 | 0.36 | 1.206 | 1.206 | 3.35 | 8.04
 | Půdorys 2.NP | ZELEZOBETONOVÁ KCE | Betonářské práce | 0 | 0 | @452@ | 1552Slo0798420303 | m3 | Sloup | EXISTING | yes | 0.6 | 0.6 | 0.36 | 1.206 | 1.206 | 3.35 | 8.04
 | Půdorys 2.NP | ZELEZOBETONOVÁ KCE | Betonářské práce | 0 | 0 | @452@ | 1552Slo0798420301 | m3 | Sloup | EXISTING | yes | 0.6 | 0.6 | 0.36 | 1.206 | 1.206 | 3.35 | 8.04
 | Půdorys 2.NP | ZELEZOBETONOVÁ KCE | Betonářské práce | 0 | 0 | @452@ | 1552Slo0798420299 | m3 | Sloup | EXISTING | yes | 0.6 | 0.6 | 0.36 | 1.206 | 1.206 | 3.35 | 8.04
 | Půdorys 2.NP | ZELEZOBETONOVÁ KCE | Betonářské práce | 0 | 0 | @452@ | 1552Slo0798420297 | m3 | Sloup | EXISTING | yes | 0.6 | 0.6 | 0.36 | 1.206 | 1.206 | 3.35 | 8.04
 | Půdorys 2.NP | ZELEZOBETONOVÁ KCE | Betonářské práce | 0 | 0 | @452@ | 1552Slo0798420295 | m3 | Sloup | EXISTING | yes | 0.6 | 0.6 | 0.36 | 1.206 | 1.206 | 3.35 | 8.04
 | Půdorys 2.NP | ZELEZOBETONOVÁ KCE | Betonářské práce | 0 | 0 | @452@ | 1552Slo0798420293 | m3 | Sloup | EXISTING | yes | 0.6 | 0.6 | 0.36 | 1.206 | 1.206 | 3.35 | 8.04
 | Půdorys 2.NP | ZELEZOBETONOVÁ KCE | Betonářské práce | 0 | 0 | @452@ | 1552Slo0798420291 | m3 | Sloup | EXISTING | yes | 0.6 | 0.6 | 0.36 | 1.206 | 1.206 | 3.35 | 8.04
 | Půdorys 2.NP | ZELEZOBETONOVÁ KCE | Betonářské práce | 0 | 0 | @452@ | 1552Slo0798420289 | m3 | Sloup | EXISTING | yes | 0.6 | 0.6 | 0.36 | 1.206 | 1.206 | 3.35 | 8.04
 | Půdorys 2.NP | ZELEZOBETONOVÁ KCE | Betonářské práce | 0 | 0 | @452@ | 1552Slo0798420287 | m3 | Sloup | EXISTING | yes | 0.6 | 0.6 | 0.36 | 1.206 | 1.206 | 3.35 | 8.04
 | Půdorys 2.NP | ZELEZOBETONOVÁ KCE | Betonářské práce | 0 | 0 | @452@ | 1552Slo0798420283 | m3 | Sloup | EXISTING | yes | 0.6 | 0.6 | 0.36 | 1.206 | 1.206 | 3.35 | 8.04
 | Půdorys 2.NP | ZELEZOBETONOVÁ KCE | Betonářské práce | 0 | 0 | @452@ | 1552Slo0798420277 | m3 | Sloup | EXISTING | yes | 0.4 | 0.4 | 0.16 | 0.536 | 0.536 | 3.35 | 5.36
 | Půdorys 2.NP | ZELEZOBETONOVÁ KCE | Betonářské práce | 0 | 0 | @452@ | 1552Slo0798420275 | m3 | Sloup | EXISTING | yes | 0.4 | 0.4 | 0.16 | 0.536 | 0.536 | 3.35 | 5.36
 | Půdorys 2.NP | ZELEZOBETONOVÁ KCE | Betonářské práce | 0 | 0 | @452@ | 1552Slo0798420273 | m3 | Sloup | EXISTING | yes | 0.4 | 0.4 | 0.16 | 0.536 | 0.536 | 3.35 | 5.36
 | Půdorys 2.NP | ZELEZOBETONOVÁ KCE | Betonářské práce | 0 | 0 | @452@ | 1552Slo0798420271 | m3 | Sloup | EXISTING | yes | 0.4 | 0.4 | 0.16 | 0.536 | 0.536 | 3.35 | 5.36
 | Půdorys 2.NP | ZELEZOBETONOVÁ KCE | Betonářské práce | 0 | 0 | @452@ | 1552Slo0798420269 | m3 | Sloup | EXISTING | yes | 0.4 | 0.4 | 0.16 | 0.536 | 0.536 | 3.35 | 5.36
 | Půdorys 2.NP | ZELEZOBETONOVÁ KCE | Betonářské práce | 0 | 0 | @452@ | 1552Slo0798420265 | m3 | Sloup | EXISTING | yes | 0.4 | 0.4 | 0.16 | 0.536 | 0.536 | 3.35 | 5.36
 | Půdorys 2.NP | ZELEZOBETONOVÁ KCE | Betonářské práce | 0 | 0 | @452@ | 1552Slo0798420263 | m3 | Sloup | EXISTING | yes | 0.4 | 0.4 | 0.16 | 0.536 | 0.536 | 3.35 | 5.36
 | Půdorys 2.NP | ZELEZOBETONOVÁ KCE | Betonářské práce | 0 | 0 | @452@ | 1552Slo0798420261 | m3 | Sloup | EXISTING | yes | 0.4 | 0.4 | 0.16 | 0.536 | 0.536 | 3.35 | 5.36
 | Půdorys 2.NP | ZELEZOBETONOVÁ KCE | Betonářské práce | 0 | 0 | @452@ | 1552Slo0798420259 | m3 | Sloup | EXISTING | yes | 0.4 | 0.4 | 0.16 | 0.536 | 0.536 | 3.35 | 5.36
 | Půdorys 2.NP | ZELEZOBETONOVÁ KCE | Betonářské práce | 0 | 0 | @452@ | 1552Slo0798420285 | m3 | Sloup | EXISTING | yes | 0.6 | 0.6 | 0.36 | 1.206 | 1.206 | 3.35 | 8.04
 | Půdorys 2.NP | ZELEZOBETONOVÁ KCE | Betonářské práce | 0 | 0 | @452@ | 1552Slo0798420307 | m3 | Sloup | EXISTING | yes | 0.6 | 0.6 | 0.36 | 1.206 | 1.206 | 3.35 | 8.04
 | Půdorys 2.NP | ZELEZOBETONOVÁ KCE | Betonářské práce | 0 | 0 | @452@ | 1552Slo0798420341 | m3 | Sloup | EXISTING | yes | 0.6 | 0.6 | 0.36 | 1.206 | 1.206 | 3.35 | 8.04
 | Půdorys 2.NP | ZELEZOBETONOVÁ KCE | Betonářské práce | 0 | 0 | @452@ | 1552Slo0798420305 | m3 | Sloup | EXISTING | yes | 0.6 | 0.6 | 0.36 | 1.206 | 1.206 | 3.35 | 8.04
 | Půdorys 2.NP | ZELEZOBETONOVÁ KCE | Betonářské práce | 0 | 0 | @452@ | 1552Slo0798420401 | m3 | Sloup | EXISTING | yes | 0.6 | 0.6 | 0.36 | 1.206 | 1.206 | 3.35 | 8.04
 | Půdorys 2.NP | ZELEZOBETONOVÁ KCE | Betonářské práce | 0 | 0 | @452@ | 1552Slo0798420399 | m3 | Sloup | EXISTING | yes | 0.6 | 0.4 | 0.24 | 0.804 | 0.804 | 3.35 | 6.7
 | Půdorys 2.NP | ZELEZOBETONOVÁ KCE | Betonářské práce | 0 | 0 | @452@ | 1552Slo0000001784 | m3 | Sloup | EXISTING | yes | 0.4 | 0.4 | 0.16 | 0.536 | 0.536 | 3.35 | 5.36
 | Půdorys 2.NP | ZELEZOBETONOVÁ KCE | Betonářské práce | 0 | 0 | @452@ | 1552Slo0000001776 | m3 | Sloup | EXISTING | yes | 0.4 | 0.4 | 0.16 | 0.536 | 0.536 | 3.35 | 5.36
 | Půdorys 2.NP | ZELEZOBETONOVÁ KCE | Betonářské práce | 0 | 0 | @452@ | 1552Slo0000001780 | m3 | Sloup | EXISTING | yes | 0.4 | 0.4 | 0.16 | 0.536 | 0.536 | 3.35 | 5.36
 | Půdorys 2.NP | ZELEZOBETONOVÁ KCE | Betonářské práce | 0 | 0 | @452@ | 1552Slo0000001774 | m3 | Sloup | EXISTING | yes | 0.4 | 0.4 | 0.16 | 0.536 | 0.536 | 3.35 | 5.36
 | Půdorys 2.NP | ZELEZOBETONOVÁ KCE | Betonářské práce | 0 | 0 | @452@ | 1552Slo0000001808 | m3 | Sloup | EXISTING | yes | 0.4 | 0.4 | 0.16 | 0.536 | 0.536 | 3.35 | 5.36
 | Půdorys 2.NP | ZELEZOBETONOVÁ KCE | Betonářské práce | 0 | 0 | @452@ | 1552Slo0000001804 | m3 | Sloup | EXISTING | yes | 0.4 | 0.4 | 0.16 | 0.536 | 0.536 | 3.35 | 5.36
 | Půdorys 2.NP | ZELEZOBETONOVÁ KCE | Betonářské práce | 0 | 0 | @452@ | 1552Slo0000001812 | m3 | Sloup | EXISTING | yes | 0.4 | 0.4 | 0.16 | 0.536 | 0.536 | 3.35 | 5.36
 | Půdorys 2.NP | ZELEZOBETONOVÁ KCE | Betonářské práce | 0 | 0 | @452@ | 1552Slo0798422214 | m3 | Sloup | EXISTING | yes | 0.6 | 0.4 | 0.24 | 0.804 | 0.804 | 3.35 | 6.7
 | Půdorys 2.NP | ZELEZOBETONOVÁ KCE | Betonářské práce | 0 | 0 | @452@ | 1552Slo0798422212 | m3 | Sloup | EXISTING | yes | 0.6 | 0.4 | 0.24 | 0.804 | 0.804 | 3.35 | 6.7
 | Půdorys 2.NP | ZELEZOBETONOVÁ KCE | Betonářské práce | 0 | 0 | @452@ | 1552Slo0798422210 | m3 | Sloup | EXISTING | yes | 0.6 | 0.4 | 0.24 | 0.804 | 0.804 | 3.35 | 6.7
 | Půdorys 2.NP | ZELEZOBETONOVÁ KCE | Betonářské práce | 0 | 0 | @452@ | 1552Slo0798422216 | m3 | Sloup | EXISTING | yes | 0.6 | 0.4 | 0.24 | 0.804 | 0.804 | 3.35 | 6.7
 | Půdorys 2.NP | ZELEZOBETONOVÁ KCE | Betonářské práce | 0 | 0 | @452@ | 1552Slo0000001790 | m3 | Sloup | EXISTING | yes | 0.4 | 0.4 | 0.16 | 0.536 | 0.536 | 3.35 | 5.36
 | Půdorys 2.NP | ZELEZOBETONOVÁ KCE | Betonářské práce | 0 | 0 | @452@ | 1552Slo0798420337 | m3 | Sloup | EXISTING | yes | 0.6 | 0.4 | 0.24 | 0.804 | 0.804 | 3.35 | 6.7
 | Půdorys 2.NP | ZELEZOBETONOVÁ KCE | Betonářské práce | 0 | 0 | @452@ | 1552Slo0000001800 | m3 | Sloup | EXISTING | yes | 0.4 | 0.4 | 0.16 | 0.536 | 0.536 | 3.35 | 5.36
 | Půdorys 2.NP | ZELEZOBETONOVÁ KCE | Betonářské práce | 0 | 0 | @452@ | 1552Slo0000001796 | m3 | Sloup | EXISTING | yes | 0.4 | 0.4 | 0.16 | 0.536 | 0.536 | 3.35 | 5.36
 | Půdorys 2.NP | ZELEZOBETONOVÁ KCE | Betonářské práce | 0 | 0 | @452@ | 1552Slo0000001798 | m3 | Sloup | EXISTING | yes | 0.4 | 0.4 | 0.16 | 0.536 | 0.536 | 3.35 | 5.36
 | Půdorys 2.NP | ZELEZOBETONOVÁ KCE | Betonářské práce | 0 | 0 | @452@ | 1552Slo0000001802 | m3 | Sloup | EXISTING | yes | 0.4 | 0.4 | 0.16 | 0.536 | 0.536 | 3.35 | 5.36
 | Půdorys 2.NP | ZELEZOBETONOVÁ KCE | Betonářské práce | 0 | 0 | @452@ | 1552Slo0798420430 | m3 | Sloup | EXISTING | yes | 0.6 | 0.4 | 0.24 | 0.804 | 0.804 | 3.35 | 6.7
 | Půdorys 2.NP | ZELEZOBETONOVÁ KCE | Betonářské práce | 0 | 0 | @452@ | 1552Slo0798420333 | m3 | Sloup | EXISTING | yes | 0.6 | 0.4 | 0.24 | 0.804 | 0.804 | 3.35 | 6.7
 | Půdorys 2.NP | ZELEZOBETONOVÁ KCE | Betonářské práce | 0 | 0 | @452@ | 1552Slo0798420339 | m3 | Sloup | EXISTING | yes | 0.6 | 0.4 | 0.24 | 0.804 | 0.804 | 3.35 | 6.7
 | Půdorys 2.NP | ZELEZOBETONOVÁ KCE | Betonářské práce | 0 | 0 | @452@ | 1552Slo0798420267 | m3 | Sloup | EXISTING | yes | 0.4 | 0.4 | 0.16 | 0.536 | 0.536 | 3.35 | 5.36
 | Půdorys 2.NP | ZELEZOBETONOVÁ KCE | Betonářské práce | 0 | 0 | @452@ | 1552Slo0798422381 | m3 | Sloup | EXISTING | yes | 0.4 | 0.4 | 0.16 | 0.536 | 0.536 | 3.35 | 5.36
 | Půdorys 2.NP | ZELEZOBETONOVÁ KCE | Betonářské práce | 0 | 0 | @452@ | 1552Slo0798422440 | m3 | Sloup | EXISTING | yes | 0.6 | 0.4 | 0.24 | 0.804 | 0.804 | 3.35 | 6.7
 | Půdorys 2.NP | ZELEZOBETONOVÁ KCE | Betonářské práce | 0 | 0 | @452@ | 1552Slo0798422372 | m3 | Sloup | EXISTING | yes | 0.4 | 0.4 | 0.16 | 0.536 | 0.536 | 3.35 | 5.36
 | Půdorys 2.NP | ZELEZOBETONOVÁ KCE | Betonářské práce | 0 | 0 | @452@ | 1552Slo0798422436 | m3 | Sloup | EXISTING | yes | 0.6 | 0.4 | 0.24 | 0.804 | 0.804 | 3.35 | 6.7
 | Půdorys 2.NP | ZELEZOBETONOVÁ KCE | Betonářské práce | 0 | 0 | @452@ | 1552Slo0798422444 | m3 | Sloup | EXISTING | yes | 0.4 | 0.4 | 0.16 | 0.536 | 0.536 | 3.35 | 5.36
 | Půdorys 2.NP | ZELEZOBETONOVÁ KCE | Betonářské práce | 0 | 0 | @452@ | 1552Slo0798422385 | m3 | Sloup | EXISTING | yes | 0.4 | 0.4 | 0.16 | 0.536 | 0.536 | 3.35 | 5.36
 | Půdorys 2.NP | ZELEZOBETONOVÁ KCE | Betonářské práce | 0 | 0 | @452@ | 1552Slo0798423245 | m3 | Sloup | EXISTING | yes | 0.4 | 0.4 | 0.16 | 0.536 | 0.536 | 3.35 | 5.36
 | Půdorys 2.NP | ZELEZOBETONOVÁ KCE | Betonářské práce | 0 | 0 | @452@ | 1552Slo0798422446 | m3 | Sloup | EXISTING | yes | 0.4 | 0.4 | 0.16 | 0.536 | 0.536 | 3.35 | 5.36
 | Půdorys 2.NP | ZELEZOBETONOVÁ KCE | Betonářské práce | 0 | 0 | @452@ | 1552Slo0798422457 | m3 | Sloup | EXISTING | yes | 0.6 | 0.4 | 0.24 | 0.804 | 0.804 | 3.35 | 6.7
 | Půdorys 2.NP | ZELEZOBETONOVÁ KCE | Betonářské práce | 0 | 0 | @452@ | 1552Slo0798422461 | m3 | Sloup | EXISTING | yes | 0.6 | 0.6 | 0.36 | 1.206 | 1.206 | 3.35 | 8.04
 | Půdorys 2.NP | ZELEZOBETONOVÁ KCE | Betonářské práce | 0 | 0 | @452@ | 1552Slo0798423216 | m3 | Sloup | EXISTING | yes | 0.4 | 0.4 | 0.16 | 0.536 | 0.536 | 3.35 | 5.36
 | Půdorys 2.NP | ZELEZOBETONOVÁ KCE | Betonářské práce | 0 | 0 | @452@ | 1552Slo0798422451 | m3 | Sloup | EXISTING | yes | 0.4 | 0.4 | 0.16 | 0.536 | 0.536 | 3.35 | 5.36
 | Půdorys 2.NP | ZELEZOBETONOVÁ KCE | Betonářské práce | 0 | 0 | @452@ | 1552Slo0798423688 | m3 | Sloup | EXISTING | yes | 0.4 | 0.4 | 0.16 | 0.536 | 0.536 | 3.35 | 5.36
 | Půdorys 2.NP | ZELEZOBETONOVÁ KCE | Betonářské práce | 0 | 0 | @452@ | 1552Slo0000001778 | m3 | Sloup | EXISTING | yes | 0.4 | 0.4 | 0.16 | 0.536 | 0.536 | 3.35 | 5.36
 | Půdorys 2.NP | ZELEZOBETONOVÁ KCE | Betonářské práce | 0 | 0 | @452@ | 1552Slo0000001806 | m3 | Sloup | EXISTING | yes | 0.4 | 0.4 | 0.16 | 0.536 | 0.536 | 3.35 | 5.36
 | Půdorys 2.NP | ZELEZOBETONOVÁ KCE | Betonářské práce | 0 | 0 | @452@ | 1552Slo0000001788 | m3 | Sloup | EXISTING | yes | 0.4 | 0.4 | 0.16 | 0.536 | 0.536 | 3.35 | 5.36
 | Půdorys 2.NP | ZELEZOBETONOVÁ KCE | Betonářské práce | 0 | 0 | @452@ | 1552Slo0798420335 | m3 | Sloup | EXISTING | yes | 0.6 | 0.4 | 0.24 | 0.804 | 0.804 | 3.35 | 6.7
 | Půdorys 2.NP | ZELEZOBETONOVÁ KCE | Betonářské práce | 0 | 0 | @452@ | 1552Slo0000001810 | m3 | Sloup | EXISTING | yes | 0.4 | 0.4 | 0.16 | 0.536 | 0.536 | 3.35 | 5.36
 | Půdorys 2.NP | ZELEZOBETONOVÁ KCE | Betonářské práce | 0 | 0 | @452@ | 1552Slo0000001786 | m3 | Sloup | EXISTING | yes | 0.4 | 0.4 | 0.16 | 0.536 | 0.536 | 3.35 | 5.36
 | Půdorys 2.NP | ZELEZOBETONOVÁ KCE | Betonářské práce | 0 | 0 | @452@ | 1552Slo0000001782 | m3 | Sloup | EXISTING | yes | 0.4 | 0.4 | 0.16 | 0.536 | 0.536 | 3.35 | 5.36
 | Půdorys 2.NP | ZELEZOBETONOVÁ KCE | Betonářské práce | 0 | 0 | @452@ | 1552Slo0000001794 | m3 | Sloup | EXISTING | yes | 0.4 | 0.4 | 0.16 | 0.536 | 0.536 | 3.35 | 5.36
 | Půdorys 2.NP | ZELEZOBETONOVÁ KCE | Betonářské práce | 0 | 0 | @452@ | 1552Slo0798420279 | m3 | Sloup | EXISTING | yes | 0.6 | 0.6 | 0.36 | 1.206 | 1.206 | 3.35 | 8.04
 | Půdorys 2.NP | ZELEZOBETONOVÁ KCE | Betonářské práce | 0 | 0 | @452@ | 1552Slo0798420281 | m3 | Sloup | EXISTING | yes | 0.6 | 0.6 | 0.36 | 1.206 | 1.206 | 3.35 | 8.04
 | Půdorys 2.NP | ZELEZOBETONOVÁ KCE | Betonářské práce | 0 | 0 | @452@ | 1552Slo0798420488 | m3 | Sloup | EXISTING | yes | 0.6 | 0.6 | 0.36 | 1.206 | 1.206 | 3.35 | 8.04
 | Půdorys 2.NP | ZELEZOBETONOVÁ KCE | Betonářské práce | 0 | 0 | @452@ | 1552Slo0798420486 | m3 | Sloup | EXISTING | yes | 0.6 | 0.4 | 0.24 | 0.804 | 0.804 | 3.35 | 6.7
 | Půdorys 2.NP | ZELEZOBETONOVÁ KCE | Betonářské práce | 0 | 0 | @452@ | 1552Slo0798422026 | m3 | Sloup | EXISTING | yes | 0.6 | 0.4 | 0.24 | 0.804 | 0.804 | 3.35 | 6.7
 | Půdorys 3.NP | ZELEZOBETONOVÁ KCE | Betonářské práce | 0 | 0 | @452@ | 1652Slo0798426246 | m3 | Sloup | EXISTING | yes | 0.4 | 0.4 | 0.16 | 0.488 | 0.488 | 3.05 | 4.88
 | Půdorys 3.NP | ZELEZOBETONOVÁ KCE | Betonářské práce | 0 | 0 | @452@ | 1652Slo0798426244 | m3 | Sloup | EXISTING | yes | 0.4 | 0.4 | 0.16 | 0.488 | 0.488 | 3.05 | 4.88
 | Půdorys 3.NP | ZELEZOBETONOVÁ KCE | Betonářské práce | 0 | 0 | @452@ | 1652Slo0798426242 | m3 | Sloup | EXISTING | yes | 0.4 | 0.4 | 0.16 | 0.488 | 0.488 | 3.05 | 4.88
 | Půdorys 3.NP | ZELEZOBETONOVÁ KCE | Betonářské práce | 0 | 0 | @452@ | 1652Slo0798426240 | m3 | Sloup | EXISTING | yes | 0.4 | 0.4 | 0.16 | 0.488 | 0.488 | 3.05 | 4.88
 | Půdorys 3.NP | ZELEZOBETONOVÁ KCE | Betonářské práce | 0 | 0 | @452@ | 1652Slo0798426238 | m3 | Sloup | EXISTING | yes | 0.4 | 0.4 | 0.16 | 0.488 | 0.488 | 3.05 | 4.88
 | Půdorys 3.NP | ZELEZOBETONOVÁ KCE | Betonářské práce | 0 | 0 | @452@ | 1652Slo0798426236 | m3 | Sloup | EXISTING | yes | 0.4 | 0.4 | 0.16 | 0.488 | 0.488 | 3.05 | 4.88
 | Půdorys 3.NP | ZELEZOBETONOVÁ KCE | Betonářské práce | 0 | 0 | @452@ | 1652Slo0798426234 | m3 | Sloup | EXISTING | yes | 0.4 | 0.4 | 0.16 | 0.488 | 0.488 | 3.05 | 4.88
 | Půdorys 3.NP | ZELEZOBETONOVÁ KCE | Betonářské práce | 0 | 0 | @452@ | 1652Slo0798426232 | m3 | Sloup | EXISTING | yes | 0.4 | 0.4 | 0.16 | 0.488 | 0.488 | 3.05 | 4.88
 | Půdorys 3.NP | ZELEZOBETONOVÁ KCE | Betonářské práce | 0 | 0 | @452@ | 1652Slo0798426230 | m3 | Sloup | EXISTING | yes | 0.4 | 0.4 | 0.16 | 0.488 | 0.488 | 3.05 | 4.88
 | Půdorys 3.NP | ZELEZOBETONOVÁ KCE | Betonářské práce | 0 | 0 | @452@ | 1652Slo0798426228 | m3 | Sloup | EXISTING | yes | 0.4 | 0.4 | 0.16 | 0.488 | 0.488 | 3.05 | 4.88
 | Půdorys 3.NP | ZELEZOBETONOVÁ KCE | Betonářské práce | 0 | 0 | @452@ | 1652Slo0798426142 | m3 | Sloup | EXISTING | yes | 0.4 | 0.4 | 0.16 | 0.488 | 0.488 | 3.05 | 4.88
 | Půdorys 3.NP | ZELEZOBETONOVÁ KCE | Betonářské práce | 0 | 0 | @452@ | 1652Slo0798426176 | m3 | Sloup | EXISTING | yes | 0.4 | 0.4 | 0.16 | 0.488 | 0.488 | 3.05 | 4.88
 | Půdorys 3.NP | ZELEZOBETONOVÁ KCE | Betonářské práce | 0 | 0 | @452@ | 1652Slo0798426178 | m3 | Sloup | EXISTING | yes | 0.4 | 0.4 | 0.16 | 0.488 | 0.488 | 3.05 | 4.88
 | Půdorys 3.NP | ZELEZOBETONOVÁ KCE | Betonářské práce | 0 | 0 | @452@ | 1652Slo0798426180 | m3 | Sloup | EXISTING | yes | 0.4 | 0.4 | 0.16 | 0.488 | 0.488 | 3.05 | 4.88
 | Půdorys 3.NP | ZELEZOBETONOVÁ KCE | Betonářské práce | 0 | 0 | @452@ | 1652Slo0798426182 | m3 | Sloup | EXISTING | yes | 0.4 | 0.4 | 0.16 | 0.488 | 0.488 | 3.05 | 4.88
 | Půdorys 3.NP | ZELEZOBETONOVÁ KCE | Betonářské práce | 0 | 0 | @452@ | 1652Slo0798426184 | m3 | Sloup | EXISTING | yes | 0.4 | 0.4 | 0.16 | 0.488 | 0.488 | 3.05 | 4.88
 | Půdorys 3.NP | ZELEZOBETONOVÁ KCE | Betonářské práce | 0 | 0 | @452@ | 1652Slo0798426186 | m3 | Sloup | EXISTING | yes | 0.4 | 0.4 | 0.16 | 0.488 | 0.488 | 3.05 | 4.88
 | Půdorys 3.NP | ZELEZOBETONOVÁ KCE | Betonářské práce | 0 | 0 | @452@ | 1652Slo0798426188 | m3 | Sloup | EXISTING | yes | 0.4 | 0.4 | 0.16 | 0.488 | 0.488 | 3.05 | 4.88
 | Půdorys 3.NP | ZELEZOBETONOVÁ KCE | Betonářské práce | 0 | 0 | @452@ | 1652Slo0798426190 | m3 | Sloup | EXISTING | yes | 0.4 | 0.4 | 0.16 | 0.488 | 0.488 | 3.05 | 4.88
 | Půdorys 3.NP | ZELEZOBETONOVÁ KCE | Betonářské práce | 0 | 0 | @452@ | 1652Slo0798426192 | m3 | Sloup | EXISTING | yes | 0.4 | 0.4 | 0.16 | 0.488 | 0.488 | 3.05 | 4.88
 | Půdorys 3.NP | ZELEZOBETONOVÁ KCE | Betonářské práce | 0 | 0 | @452@ | 1652Slo0798426194 | m3 | Sloup | EXISTING | yes | 0.4 | 0.4 | 0.16 | 0.488 | 0.488 | 3.05 | 4.88
 | Půdorys 3.NP | ZELEZOBETONOVÁ KCE | Betonářské práce | 0 | 0 | @452@ | 1652Slo0798426196 | m3 | Sloup | EXISTING | yes | 0.4 | 0.4 | 0.16 | 0.488 | 0.488 | 3.05 | 4.88
 | Půdorys 3.NP | ZELEZOBETONOVÁ KCE | Betonářské práce | 0 | 0 | @452@ | 1652Slo0798426198 | m3 | Sloup | EXISTING | yes | 0.4 | 0.4 | 0.16 | 0.488 | 0.488 | 3.05 | 4.88
 | Půdorys 3.NP | ZELEZOBETONOVÁ KCE | Betonářské práce | 0 | 0 | @452@ | 1652Slo0798426206 | m3 | Sloup | EXISTING | yes | 0.4 | 0.4 | 0.16 | 0.488 | 0.488 | 3.05 | 4.88
 | Půdorys 3.NP | ZELEZOBETONOVÁ KCE | Betonářské práce | 0 | 0 | @452@ | 1652Slo0798426208 | m3 | Sloup | EXISTING | yes | 0.4 | 0.4 | 0.16 | 0.488 | 0.488 | 3.05 | 4.88
 | Půdorys 3.NP | ZELEZOBETONOVÁ KCE | Betonářské práce | 0 | 0 | @452@ | 1652Slo0798426210 | m3 | Sloup | EXISTING | yes | 0.4 | 0.4 | 0.16 | 0.488 | 0.488 | 3.05 | 4.88
 | Půdorys 3.NP | ZELEZOBETONOVÁ KCE | Betonářské práce | 0 | 0 | @452@ | 1652Slo0798426212 | m3 | Sloup | EXISTING | yes | 0.4 | 0.4 | 0.16 | 0.488 | 0.488 | 3.05 | 4.88
 | Půdorys 3.NP | ZELEZOBETONOVÁ KCE | Betonářské práce | 0 | 0 | @452@ | 1652Slo0798426214 | m3 | Sloup | EXISTING | yes | 0.4 | 0.4 | 0.16 | 0.488 | 0.488 | 3.05 | 4.88
 | Půdorys 3.NP | ZELEZOBETONOVÁ KCE | Betonářské práce | 0 | 0 | @452@ | 1652Slo0798426216 | m3 | Sloup | EXISTING | yes | 0.4 | 0.4 | 0.16 | 0.488 | 0.488 | 3.05 | 4.88
 | Půdorys 3.NP | ZELEZOBETONOVÁ KCE | Betonářské práce | 0 | 0 | @452@ | 1652Slo0798426218 | m3 | Sloup | EXISTING | yes | 0.4 | 0.4 | 0.16 | 0.488 | 0.488 | 3.05 | 4.88
 | Půdorys 3.NP | ZELEZOBETONOVÁ KCE | Betonářské práce | 0 | 0 | @452@ | 1652Slo0798426220 | m3 | Sloup | EXISTING | yes | 0.4 | 0.4 | 0.16 | 0.488 | 0.488 | 3.05 | 4.88
 | Půdorys 3.NP | ZELEZOBETONOVÁ KCE | Betonářské práce | 0 | 0 | @452@ | 1652Slo0798426224 | m3 | Sloup | EXISTING | yes | 0.4 | 0.4 | 0.16 | 0.488 | 0.488 | 3.05 | 4.88
 | Půdorys 3.NP | ZELEZOBETONOVÁ KCE | Betonářské práce | 0 | 0 | @452@ | 1652Slo0798426762 | m3 | Sloup | EXISTING | yes | 0.4 | 0.4 | 0.16 | 0.488 | 0.488 | 3.05 | 4.88
 | Půdorys 3.NP | ZELEZOBETONOVÁ KCE | Betonářské práce | 0 | 0 | @452@ | 1652Slo0798426226 | m3 | Sloup | EXISTING | yes | 0.4 | 0.4 | 0.16 | 0.488 | 0.488 | 3.05 | 4.88
 | Půdorys 3.NP | ZELEZOBETONOVÁ KCE | Betonářské práce | 0 | 0 | @452@ | 1652Slo0798426152 | m3 | Sloup | EXISTING | yes | 0.4 | 0.4 | 0.16 | 0.488 | 0.488 | 3.05 | 4.88
 | Půdorys 3.NP | ZELEZOBETONOVÁ KCE | Betonářské práce | 0 | 0 | @452@ | 1652Slo0798426757 | m3 | Sloup | EXISTING | yes | 0.4 | 0.4 | 0.16 | 0.488 | 0.488 | 3.05 | 4.88
 | Půdorys 3.NP | ZELEZOBETONOVÁ KCE | Betonářské práce | 0 | 0 | @452@ | 1652Slo0798426166 | m3 | Sloup | EXISTING | yes | 0.6 | 0.4 | 0.24 | 0.732 | 0.732 | 3.05 | 6.1
 | Půdorys 3.NP | ZELEZOBETONOVÁ KCE | Betonářské práce | 0 | 0 | @452@ | 1652Slo0798426222 | m3 | Sloup | EXISTING | yes | 0.4 | 0.4 | 0.16 | 0.488 | 0.488 | 3.05 | 4.88
 | Půdorys 3.NP | ZELEZOBETONOVÁ KCE | Betonářské práce | 0 | 0 | @452@ | 1652Slo0798426202 | m3 | Sloup | EXISTING | yes | 0.4 | 0.4 | 0.16 | 0.488 | 0.488 | 3.05 | 4.88
 | Půdorys 3.NP | ZELEZOBETONOVÁ KCE | Betonářské práce | 0 | 0 | @452@ | 1652Slo0798426200 | m3 | Sloup | EXISTING | yes | 0.4 | 0.4 | 0.16 | 0.488 | 0.488 | 3.05 | 4.88
 | Půdorys 3.NP | ZELEZOBETONOVÁ KCE | Betonářské práce | 0 | 0 | @452@ | 1652Slo0798426168 | m3 | Sloup | EXISTING | yes | 0.4 | 0.4 | 0.16 | 0.488 | 0.488 | 3.05 | 4.88
 | Půdorys 3.NP | ZELEZOBETONOVÁ KCE | Betonářské práce | 0 | 0 | @452@ | 1652Slo0798426204 | m3 | Sloup | EXISTING | yes | 0.4 | 0.4 | 0.16 | 0.488 | 0.488 | 3.05 | 4.88
 | Půdorys 3.NP | ZELEZOBETONOVÁ KCE | Betonářské práce | 0 | 0 | @452@ | 1652Slo0798426154 | m3 | Sloup | EXISTING | yes | 0.6 | 0.4 | 0.24 | 0.732 | 0.732 | 3.05 | 6.1
 | Půdorys 3.NP | ZELEZOBETONOVÁ KCE | Betonářské práce | 0 | 0 | @452@ | 1652Slo0798426693 | m3 | Sloup | EXISTING | yes | 0.6 | 0.4 | 0.24 | 0.732 | 0.732 | 3.05 | 6.1
 | Půdorys 3.NP | ZELEZOBETONOVÁ KCE | Betonářské práce | 0 | 0 | @452@ | 1652Slo0798426532 | m3 | Sloup | EXISTING | yes | 0.6 | 0.4 | 0.24 | 0.732 | 0.732 | 3.05 | 6.1
 | Půdorys 3.NP | ZELEZOBETONOVÁ KCE | Betonářské práce | 0 | 0 | @452@ | 1652Slo0798426146 | m3 | Sloup | EXISTING | yes | 0.4 | 0.4 | 0.16 | 0.488 | 0.488 | 3.05 | 4.88
 | Půdorys 3.NP | ZELEZOBETONOVÁ KCE | Betonářské práce | 0 | 0 | @452@ | 1652Slo0798426547 | m3 | Sloup | EXISTING | yes | 0.4 | 0.4 | 0.16 | 0.488 | 0.488 | 3.05 | 4.88
 | Půdorys 3.NP | ZELEZOBETONOVÁ KCE | Betonářské práce | 0 | 0 | @452@ | 1652Slo0798426549 | m3 | Sloup | EXISTING | yes | 0.4 | 0.4 | 0.16 | 0.488 | 0.488 | 3.05 | 4.88
 | Půdorys 3.NP | ZELEZOBETONOVÁ KCE | Betonářské práce | 0 | 0 | @452@ | 1652Slo0798426387 | m3 | Sloup | EXISTING | yes | 0.4 | 0.4 | 0.16 | 0.488 | 0.488 | 3.05 | 4.88
 | Půdorys 3.NP | ZELEZOBETONOVÁ KCE | Betonářské práce | 0 | 0 | @452@ | 1652Slo0798426364 | m3 | Sloup | EXISTING | yes | 0.6 | 0.4 | 0.24 | 0.732 | 0.732 | 3.05 | 6.1
 | Půdorys 3.NP | ZELEZOBETONOVÁ KCE | Betonářské práce | 0 | 0 | @452@ | 1652Slo0798426138 | m3 | Sloup | EXISTING | yes | 0.6 | 0.4 | 0.24 | 0.732 | 0.732 | 3.05 | 6.1
 | Půdorys 3.NP | ZELEZOBETONOVÁ KCE | Betonářské práce | 0 | 0 | @452@ | 1652Slo0798426370 | m3 | Sloup | EXISTING | yes | 0.6 | 0.4 | 0.24 | 0.732 | 0.732 | 3.05 | 6.1
 | Půdorys 3.NP | ZELEZOBETONOVÁ KCE | Betonářské práce | 0 | 0 | @452@ | 1652Slo0798426374 | m3 | Sloup | EXISTING | yes | 0.4 | 0.4 | 0.16 | 0.488 | 0.488 | 3.05 | 4.88
 | Půdorys 3.NP | ZELEZOBETONOVÁ KCE | Betonářské práce | 0 | 0 | @452@ | 1652Slo0798426553 | m3 | Sloup | EXISTING | yes | 0.4 | 0.4 | 0.16 | 0.488 | 0.488 | 3.05 | 4.88
 | Půdorys 3.NP | ZELEZOBETONOVÁ KCE | Betonářské práce | 0 | 0 | @452@ | 1652Slo0798426366 | m3 | Sloup | EXISTING | yes | 0.4 | 0.4 | 0.16 | 0.488 | 0.488 | 3.05 | 4.88
 | Půdorys 3.NP | ZELEZOBETONOVÁ KCE | Betonářské práce | 0 | 0 | @452@ | 1652Slo0798426381 | m3 | Sloup | EXISTING | yes | 0.4 | 0.4 | 0.16 | 0.488 | 0.488 | 3.05 | 4.88
 | Půdorys 3.NP | ZELEZOBETONOVÁ KCE | Betonářské práce | 0 | 0 | @452@ | 1652Slo0798426383 | m3 | Sloup | EXISTING | yes | 0.4 | 0.4 | 0.16 | 0.488 | 0.488 | 3.05 | 4.88
 | Půdorys 3.NP | ZELEZOBETONOVÁ KCE | Betonářské práce | 0 | 0 | @452@ | 1652Slo0798426679 | m3 | Sloup | EXISTING | yes | 0.4 | 0.4 | 0.16 | 0.488 | 0.488 | 3.05 | 4.88
 | Půdorys 3.NP | ZELEZOBETONOVÁ KCE | Betonářské práce | 0 | 0 | @452@ | 1652Slo0798426596 | m3 | Sloup | EXISTING | yes | 0.6 | 0.4 | 0.24 | 0.732 | 0.732 | 3.05 | 6.1
 | Půdorys 3.NP | ZELEZOBETONOVÁ KCE | Betonářské práce | 0 | 0 | @452@ | 1652Slo0798426594 | m3 | Sloup | EXISTING | yes | 0.6 | 0.4 | 0.24 | 0.732 | 0.732 | 3.05 | 6.1
 | Půdorys 3.NP | ZELEZOBETONOVÁ KCE | Betonářské práce | 0 | 0 | @452@ | 1652Slo0798426592 | m3 | Sloup | EXISTING | yes | 0.6 | 0.4 | 0.24 | 0.732 | 0.732 | 3.05 | 6.1
 | Půdorys 3.NP | ZELEZOBETONOVÁ KCE | Betonářské práce | 0 | 0 | @452@ | 1652Slo0798426159 | m3 | Sloup | EXISTING | yes | 0.6 | 0.4 | 0.24 | 0.732 | 0.732 | 3.05 | 6.1
 | Půdorys 3.NP | ZELEZOBETONOVÁ KCE | Betonářské práce | 0 | 0 | @452@ | 1652Slo0798426170 | m3 | Sloup | EXISTING | yes | 0.6 | 0.4 | 0.24 | 0.732 | 0.732 | 3.05 | 6.1
 | Půdorys 3.NP | ZELEZOBETONOVÁ KCE | Betonářské práce | 0 | 0 | @452@ | 1652Slo0798426172 | m3 | Sloup | EXISTING | yes | 0.6 | 0.4 | 0.24 | 0.732 | 0.732 | 3.05 | 6.1
 | Půdorys 3.NP | ZELEZOBETONOVÁ KCE | Betonářské práce | 0 | 0 | @452@ | 1652Slo0798426174 | m3 | Sloup | EXISTING | yes | 0.6 | 0.4 | 0.24 | 0.732 | 0.732 | 3.05 | 6.1
 | Půdorys 3.NP | ZELEZOBETONOVÁ KCE | Betonářské práce | 0 | 0 | @452@ | 1652Slo0798426621 | m3 | Sloup | EXISTING | yes | 0.6 | 0.4 | 0.24 | 0.732 | 0.732 | 3.05 | 6.1
 | Půdorys 4.NP | ZELEZOBETONOVÁ KCE | Betonářské práce | 0 | 0 | @452@ | 1752Slo0000010310 | m3 | Sloup | EXISTING | yes | 0.4 | 0.4 | 0.16 | 0.488 | 0.488 | 3.05 | 4.88
 | Půdorys 4.NP | ZELEZOBETONOVÁ KCE | Betonářské práce | 0 | 0 | @452@ | 1752Slo0000010308 | m3 | Sloup | EXISTING | yes | 0.4 | 0.4 | 0.16 | 0.488 | 0.488 | 3.05 | 4.88
 | Půdorys 4.NP | ZELEZOBETONOVÁ KCE | Betonářské práce | 0 | 0 | @452@ | 1752Slo0000010306 | m3 | Sloup | EXISTING | yes | 0.4 | 0.4 | 0.16 | 0.488 | 0.488 | 3.05 | 4.88
 | Půdorys 4.NP | ZELEZOBETONOVÁ KCE | Betonářské práce | 0 | 0 | @452@ | 1752Slo0000010304 | m3 | Sloup | EXISTING | yes | 0.4 | 0.4 | 0.16 | 0.488 | 0.488 | 3.05 | 4.88
 | Půdorys 4.NP | ZELEZOBETONOVÁ KCE | Betonářské práce | 0 | 0 | @452@ | 1752Slo0000010302 | m3 | Sloup | EXISTING | yes | 0.4 | 0.4 | 0.16 | 0.488 | 0.488 | 3.05 | 4.88
 | Půdorys 4.NP | ZELEZOBETONOVÁ KCE | Betonářské práce | 0 | 0 | @452@ | 1752Slo0000010300 | m3 | Sloup | EXISTING | yes | 0.4 | 0.4 | 0.16 | 0.488 | 0.488 | 3.05 | 4.88
 | Půdorys 4.NP | ZELEZOBETONOVÁ KCE | Betonářské práce | 0 | 0 | @452@ | 1752Slo0000010298 | m3 | Sloup | EXISTING | yes | 0.4 | 0.4 | 0.16 | 0.488 | 0.488 | 3.05 | 4.88
 | Půdorys 4.NP | ZELEZOBETONOVÁ KCE | Betonářské práce | 0 | 0 | @452@ | 1752Slo0000010296 | m3 | Sloup | EXISTING | yes | 0.4 | 0.4 | 0.16 | 0.488 | 0.488 | 3.05 | 4.88
 | Půdorys 4.NP | ZELEZOBETONOVÁ KCE | Betonářské práce | 0 | 0 | @452@ | 1752Slo0000010292 | m3 | Sloup | EXISTING | yes | 0.4 | 0.4 | 0.16 | 0.488 | 0.488 | 3.05 | 4.88
 | Půdorys 4.NP | ZELEZOBETONOVÁ KCE | Betonářské práce | 0 | 0 | @452@ | 1752Slo0000010290 | m3 | Sloup | EXISTING | yes | 0.4 | 0.4 | 0.16 | 0.488 | 0.488 | 3.05 | 4.88
 | Půdorys 4.NP | ZELEZOBETONOVÁ KCE | Betonářské práce | 0 | 0 | @452@ | 1752Slo0000010288 | m3 | Sloup | EXISTING | yes | 0.4 | 0.4 | 0.16 | 0.488 | 0.488 | 3.05 | 4.88
 | Půdorys 4.NP | ZELEZOBETONOVÁ KCE | Betonářské práce | 0 | 0 | @452@ | 1752Slo0000010286 | m3 | Sloup | EXISTING | yes | 0.4 | 0.4 | 0.16 | 0.488 | 0.488 | 3.05 | 4.88
 | Půdorys 4.NP | ZELEZOBETONOVÁ KCE | Betonářské práce | 0 | 0 | @452@ | 1752Slo0000010284 | m3 | Sloup | EXISTING | yes | 0.4 | 0.4 | 0.16 | 0.488 | 0.488 | 3.05 | 4.88
 | Půdorys 4.NP | ZELEZOBETONOVÁ KCE | Betonářské práce | 0 | 0 | @452@ | 1752Slo0000010282 | m3 | Sloup | EXISTING | yes | 0.4 | 0.4 | 0.16 | 0.488 | 0.488 | 3.05 | 4.88
 | Půdorys 4.NP | ZELEZOBETONOVÁ KCE | Betonářské práce | 0 | 0 | @452@ | 1752Slo0000010280 | m3 | Sloup | EXISTING | yes | 0.4 | 0.4 | 0.16 | 0.488 | 0.488 | 3.05 | 4.88
 | Půdorys 4.NP | ZELEZOBETONOVÁ KCE | Betonářské práce | 0 | 0 | @452@ | 1752Slo0000010278 | m3 | Sloup | EXISTING | yes | 0.4 | 0.4 | 0.16 | 0.488 | 0.488 | 3.05 | 4.88
 | Půdorys 4.NP | ZELEZOBETONOVÁ KCE | Betonářské práce | 0 | 0 | @452@ | 1752Slo0000010276 | m3 | Sloup | EXISTING | yes | 0.4 | 0.4 | 0.16 | 0.488 | 0.488 | 3.05 | 4.88
 | Půdorys 4.NP | ZELEZOBETONOVÁ KCE | Betonářské práce | 0 | 0 | @452@ | 1752Slo0000010274 | m3 | Sloup | EXISTING | yes | 0.4 | 0.4 | 0.16 | 0.488 | 0.488 | 3.05 | 4.88
 | Půdorys 4.NP | ZELEZOBETONOVÁ KCE | Betonářské práce | 0 | 0 | @452@ | 1752Slo0000010272 | m3 | Sloup | EXISTING | yes | 0.4 | 0.4 | 0.16 | 0.488 | 0.488 | 3.05 | 4.88
 | Půdorys 4.NP | ZELEZOBETONOVÁ KCE | Betonářské práce | 0 | 0 | @452@ | 1752Slo0000010270 | m3 | Sloup | EXISTING | yes | 0.4 | 0.4 | 0.16 | 0.488 | 0.488 | 3.05 | 4.88
 | Půdorys 4.NP | ZELEZOBETONOVÁ KCE | Betonářské práce | 0 | 0 | @452@ | 1752Slo0000010268 | m3 | Sloup | EXISTING | yes | 0.4 | 0.4 | 0.16 | 0.488 | 0.488 | 3.05 | 4.88
 | Půdorys 4.NP | ZELEZOBETONOVÁ KCE | Betonářské práce | 0 | 0 | @452@ | 1752Slo0000009729 | m3 | Sloup | EXISTING | yes | 0.4 | 0.4 | 0.16 | 0.488 | 0.488 | 3.05 | 4.88
 | Půdorys 4.NP | ZELEZOBETONOVÁ KCE | Betonářské práce | 0 | 0 | @452@ | 1752Slo0000009727 | m3 | Sloup | EXISTING | yes | 0.4 | 0.4 | 0.16 | 0.488 | 0.488 | 3.05 | 4.88
 | Půdorys 4.NP | ZELEZOBETONOVÁ KCE | Betonářské práce | 0 | 0 | @452@ | 1752Slo0000009725 | m3 | Sloup | EXISTING | yes | 0.4 | 0.4 | 0.16 | 0.488 | 0.488 | 3.05 | 4.88
 | Půdorys 4.NP | ZELEZOBETONOVÁ KCE | Betonářské práce | 0 | 0 | @452@ | 1752Slo0000009723 | m3 | Sloup | EXISTING | yes | 0.4 | 0.4 | 0.16 | 0.488 | 0.488 | 3.05 | 4.88
 | Půdorys 4.NP | ZELEZOBETONOVÁ KCE | Betonářské práce | 0 | 0 | @452@ | 1752Slo0000009721 | m3 | Sloup | EXISTING | yes | 0.4 | 0.4 | 0.16 | 0.488 | 0.488 | 3.05 | 4.88
 | Půdorys 4.NP | ZELEZOBETONOVÁ KCE | Betonářské práce | 0 | 0 | @452@ | 1752Slo0000009719 | m3 | Sloup | EXISTING | yes | 0.4 | 0.4 | 0.16 | 0.488 | 0.488 | 3.05 | 4.88
 | Půdorys 4.NP | ZELEZOBETONOVÁ KCE | Betonářské práce | 0 | 0 | @452@ | 1752Slo0000009717 | m3 | Sloup | EXISTING | yes | 0.4 | 0.4 | 0.16 | 0.488 | 0.488 | 3.05 | 4.88
 | Půdorys 4.NP | ZELEZOBETONOVÁ KCE | Betonářské práce | 0 | 0 | @452@ | 1752Slo0000009715 | m3 | Sloup | EXISTING | yes | 0.4 | 0.4 | 0.16 | 0.488 | 0.488 | 3.05 | 4.88
 | Půdorys 4.NP | ZELEZOBETONOVÁ KCE | Betonářské práce | 0 | 0 | @452@ | 1752Slo0000009713 | m3 | Sloup | EXISTING | yes | 0.4 | 0.4 | 0.16 | 0.488 | 0.488 | 3.05 | 4.88
 | Půdorys 4.NP | ZELEZOBETONOVÁ KCE | Betonářské práce | 0 | 0 | @452@ | 1752Slo0000009711 | m3 | Sloup | EXISTING | yes | 0.4 | 0.4 | 0.16 | 0.488 | 0.488 | 3.05 | 4.88
 | Půdorys 4.NP | ZELEZOBETONOVÁ KCE | Betonářské práce | 0 | 0 | @452@ | 1752Slo0000010266 | m3 | Sloup | EXISTING | yes | 0.4 | 0.4 | 0.16 | 0.488 | 0.488 | 3.05 | 4.88
 | Půdorys 4.NP | ZELEZOBETONOVÁ KCE | Betonářské práce | 0 | 0 | @452@ | 1752Slo0000010341 | m3 | Sloup | EXISTING | yes | 0.4 | 0.4 | 0.16 | 0.488 | 0.488 | 3.05 | 4.88
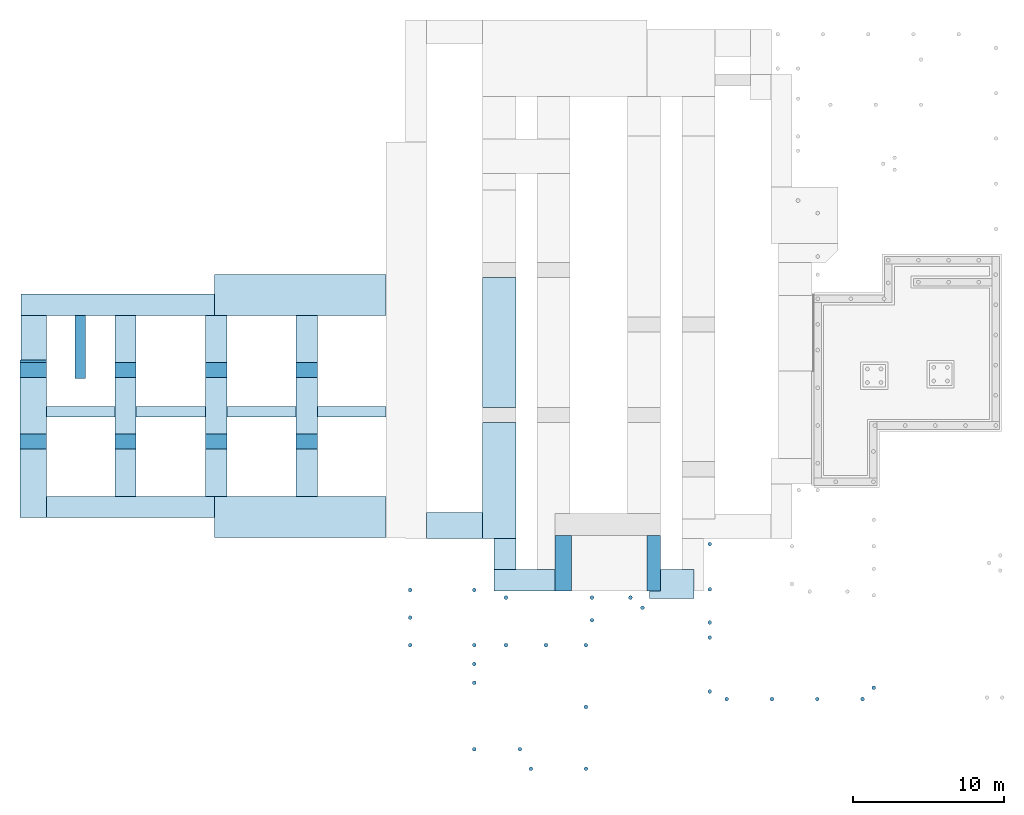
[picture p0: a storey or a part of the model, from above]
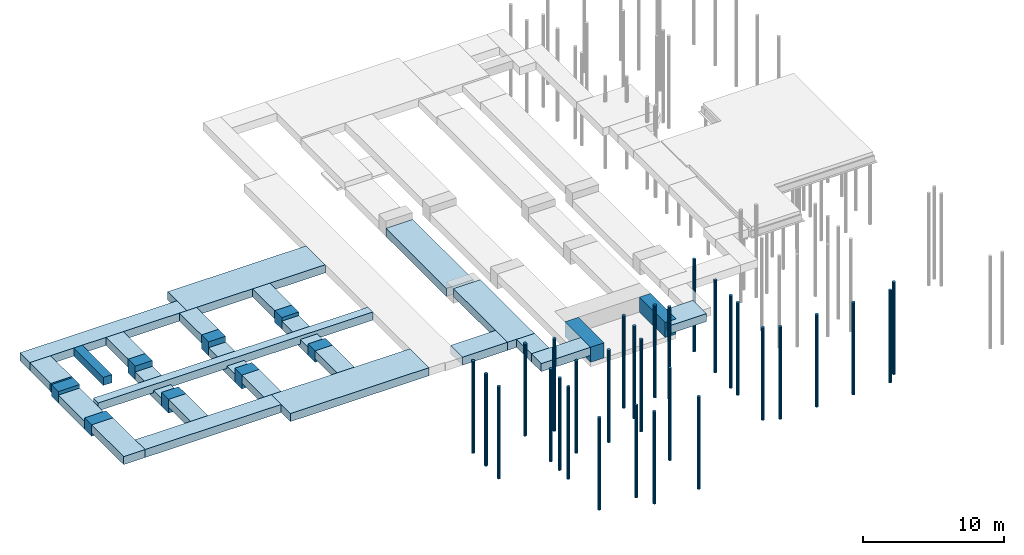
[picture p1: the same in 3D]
Properties of the parts of a building model (IFC4), part 5 of 45

# IfcColumn (605)
Name | In | Material = Materiál | Práce | Stupeň vyztužení | Číslo parkovacího místa | LOD | Allright_Stavebni_dil_ID | Jednotka | Název_objektu | Status | LoadBearing | Width (m) | Depth (m) | CrossSectionArea (m2) | GrossVolume (m3) | NetVolume (m3) | Length (m) | OuterSurfaceArea (m2)
 | Půdorys 4.NP | ZELEZOBETONOVÁ KCE | Betonářské práce | 0 | 0 | @452@ | 1752Slo0000010107 | m3 | Sloup | EXISTING | yes | 0.4 | 0.4 | 0.16 | 0.488 | 0.488 | 3.05 | 4.88
 | Půdorys 4.NP | ZELEZOBETONOVÁ KCE | Betonářské práce | 0 | 0 | @452@ | 1752Slo0000010493 | m3 | Sloup | EXISTING | yes | 0.4 | 0.4 | 0.16 | 0.488 | 0.488 | 3.05 | 4.88
 | Půdorys 4.NP | ZELEZOBETONOVÁ KCE | Betonářské práce | 0 | 0 | @452@ | 1752Slo0000010503 | m3 | Sloup | EXISTING | yes | 0.4 | 0.4 | 0.16 | 0.488 | 0.488 | 3.05 | 4.88
 | Půdorys 4.NP | ZELEZOBETONOVÁ KCE | Betonářské práce | 0 | 0 | @452@ | 1752Slo0000010294 | m3 | Sloup | EXISTING | yes | 0.4 | 0.4 | 0.16 | 0.488 | 0.488 | 3.05 | 4.88
 | Půdorys 4.NP | ZELEZOBETONOVÁ KCE | Betonářské práce | 0 | 0 | @452@ | 1752Slo0000010264 | m3 | Sloup | EXISTING | yes | 0.4 | 0.4 | 0.16 | 0.488 | 0.488 | 3.05 | 4.88
 | Půdorys 4.NP | ZELEZOBETONOVÁ KCE | Betonářské práce | 0 | 0 | @452@ | 1752Slo0000009943 | m3 | Sloup | EXISTING | yes | 0.6 | 0.4 | 0.24 | 0.732 | 0.732 | 3.05 | 6.1
 | Půdorys 4.NP | ZELEZOBETONOVÁ KCE | Betonářské práce | 0 | 0 | @452@ | 1752Slo0000009737 | m3 | Sloup | EXISTING | yes | 0.6 | 0.4 | 0.24 | 0.732 | 0.732 | 3.05 | 6.1
 | Půdorys 4.NP | ZELEZOBETONOVÁ KCE | Betonářské práce | 0 | 0 | @452@ | 1752Slo0000009705 | m3 | Sloup | EXISTING | yes | 0.6 | 0.4 | 0.24 | 0.732 | 0.732 | 3.05 | 6.1
 | Půdorys 4.NP | ZELEZOBETONOVÁ KCE | Betonářské práce | 0 | 0 | @452@ | 1752Slo0000010314 | m3 | Sloup | EXISTING | yes | 0.4 | 0.4 | 0.16 | 0.488 | 0.488 | 3.05 | 4.88
 | Půdorys 4.NP | ZELEZOBETONOVÁ KCE | Betonářské práce | 0 | 0 | @452@ | 1752Slo0000009731 | m3 | Sloup | EXISTING | yes | 0.4 | 0.4 | 0.16 | 0.488 | 0.488 | 3.05 | 4.88
 | Půdorys 4.NP | ZELEZOBETONOVÁ KCE | Betonářské práce | 0 | 0 | @452@ | 1752Slo0000009890 | m3 | Sloup | EXISTING | yes | 0.4 | 0.4 | 0.16 | 0.488 | 0.488 | 3.05 | 4.88
 | Půdorys 4.NP | ZELEZOBETONOVÁ KCE | Betonářské práce | 0 | 0 | @452@ | 1752Slo0000009699 | m3 | Sloup | EXISTING | yes | 0.6 | 0.4 | 0.24 | 0.732 | 0.732 | 3.05 | 6.1
 | Půdorys 4.NP | ZELEZOBETONOVÁ KCE | Betonářské práce | 0 | 0 | @452@ | 1752Slo0000009703 | m3 | Sloup | EXISTING | yes | 0.4 | 0.4 | 0.16 | 0.488 | 0.488 | 3.05 | 4.88
 | Půdorys 4.NP | ZELEZOBETONOVÁ KCE | Betonářské práce | 0 | 0 | @452@ | 1752Slo0000009691 | m3 | Sloup | EXISTING | yes | 0.4 | 0.4 | 0.16 | 0.488 | 0.488 | 3.05 | 4.88
 | Půdorys 4.NP | ZELEZOBETONOVÁ KCE | Betonářské práce | 0 | 0 | @452@ | 1752Slo0000009693 | m3 | Sloup | EXISTING | yes | 0.4 | 0.4 | 0.16 | 0.488 | 0.488 | 3.05 | 4.88
 | Půdorys 4.NP | ZELEZOBETONOVÁ KCE | Betonářské práce | 0 | 0 | @452@ | 1752Slo0000009683 | m3 | Sloup | EXISTING | yes | 0.4 | 0.4 | 0.16 | 0.488 | 0.488 | 3.05 | 4.88
 | Půdorys 4.NP | ZELEZOBETONOVÁ KCE | Betonářské práce | 0 | 0 | @452@ | 1752Slo0000009685 | m3 | Sloup | EXISTING | yes | 0.4 | 0.4 | 0.16 | 0.488 | 0.488 | 3.05 | 4.88
 | Půdorys 4.NP | ZELEZOBETONOVÁ KCE | Betonářské práce | 0 | 0 | @452@ | 1752Slo0000009687 | m3 | Sloup | EXISTING | yes | 0.4 | 0.4 | 0.16 | 0.488 | 0.488 | 3.05 | 4.88
 | Půdorys 4.NP | ZELEZOBETONOVÁ KCE | Betonářské práce | 0 | 0 | @452@ | 1752Slo0000009681 | m3 | Sloup | EXISTING | yes | 0.4 | 0.4 | 0.16 | 0.232 | 0.232 | 1.45 | 2.32
 | Půdorys 4.NP | ZELEZOBETONOVÁ KCE | Betonářské práce | 0 | 0 | @452@ | 1752Slo0000010312 | m3 | Sloup | EXISTING | yes | 0.4 | 0.4 | 0.16 | 0.488 | 0.488 | 3.05 | 4.88
 | Půdorys 4.NP | ZELEZOBETONOVÁ KCE | Betonářské práce | 0 | 0 | @452@ | 1752Slo0000010507 | m3 | Sloup | EXISTING | yes | 0.4 | 0.4 | 0.16 | 0.488 | 0.488 | 3.05 | 4.88
 | Půdorys 4.NP | ZELEZOBETONOVÁ KCE | Betonářské práce | 0 | 0 | @452@ | 1752Slo0000010517 | m3 | Sloup | EXISTING | yes | 0.4 | 0.4 | 0.16 | 0.488 | 0.488 | 3.05 | 4.88
 | Půdorys 4.NP | ZELEZOBETONOVÁ KCE | Betonářské práce | 0 | 0 | @452@ | 1752Slo0000010521 | m3 | Sloup | EXISTING | yes | 0.4 | 0.4 | 0.16 | 0.488 | 0.488 | 3.05 | 4.88
 | Půdorys 4.NP | ZELEZOBETONOVÁ KCE | Betonářské práce | 0 | 0 | @452@ | 1752Slo0000010515 | m3 | Sloup | EXISTING | yes | 0.4 | 0.4 | 0.16 | 0.488 | 0.488 | 3.05 | 4.88
 | Půdorys 4.NP | ZELEZOBETONOVÁ KCE | Betonářské práce | 0 | 0 | @452@ | 1752Slo0000010509 | m3 | Sloup | EXISTING | yes | 0.4 | 0.4 | 0.16 | 0.488 | 0.488 | 3.05 | 4.88
 | Půdorys 4.NP | ZELEZOBETONOVÁ KCE | Betonářské práce | 0 | 0 | @452@ | 1752Slo0000010513 | m3 | Sloup | EXISTING | yes | 0.4 | 0.4 | 0.16 | 0.488 | 0.488 | 3.05 | 4.88
 | Půdorys 4.NP | ZELEZOBETONOVÁ KCE | Betonářské práce | 0 | 0 | @452@ | 1752Slo0000010511 | m3 | Sloup | EXISTING | yes | 0.4 | 0.4 | 0.16 | 0.488 | 0.488 | 3.05 | 4.88
 | Půdorys 4.NP | ZELEZOBETONOVÁ KCE | Betonářské práce | 0 | 0 | @452@ | 1752Slo0000010109 | m3 | Sloup | EXISTING | yes | 0.4 | 0.4 | 0.16 | 0.488 | 0.488 | 3.05 | 4.88
 | Půdorys 4.NP | ZELEZOBETONOVÁ KCE | Betonářské práce | 0 | 0 | @452@ | 1752Slo0000010456 | m3 | Sloup | EXISTING | yes | 0.4 | 0.4 | 0.16 | 0.488 | 0.488 | 3.05 | 4.88
 | Půdorys 4.NP | ZELEZOBETONOVÁ KCE | Betonářské práce | 0 | 0 | @452@ | 1752Slo0000010454 | m3 | Sloup | EXISTING | yes | 0.4 | 0.4 | 0.16 | 0.488 | 0.488 | 3.05 | 4.88
 | Půdorys 4.NP | ZELEZOBETONOVÁ KCE | Betonářské práce | 0 | 0 | @452@ | 1752Slo0000010452 | m3 | Sloup | EXISTING | yes | 0.4 | 0.4 | 0.16 | 0.488 | 0.488 | 3.05 | 4.88
 | Půdorys 4.NP | ZELEZOBETONOVÁ KCE | Betonářské práce | 0 | 0 | @452@ | 1752Slo0000010450 | m3 | Sloup | EXISTING | yes | 0.4 | 0.4 | 0.16 | 0.488 | 0.488 | 3.05 | 4.88
 | Půdorys 4.NP | ZELEZOBETONOVÁ KCE | Betonářské práce | 0 | 0 | @452@ | 1752Slo0000010519 | m3 | Sloup | EXISTING | yes | 0.4 | 0.4 | 0.16 | 0.488 | 0.488 | 3.05 | 4.88
 | Půdorys 5.NP | ZELEZOBETONOVÁ KCE | Betonářské práce | 0 | 0 | @452@ | 1852Slo0000010686 | m3 | Sloup | EXISTING | yes | 0.4 | 0.4 | 0.16 | 0.632 | 0.632 | 3.95 | 6.32
 | Půdorys 5.NP | ZELEZOBETONOVÁ KCE | Betonářské práce | 0 | 0 | @452@ | 1852Slo0000010689 | m3 | Sloup | EXISTING | yes | 0.4 | 0.4 | 0.16 | 0.632 | 0.632 | 3.95 | 6.32
 | Půdorys 5.NP | ZELEZOBETONOVÁ KCE | Betonářské práce | 0 | 0 | @452@ | 1852Slo0000010752 | m3 | Sloup | EXISTING | yes | 0.4 | 0.4 | 0.16 | 0.632 | 0.632 | 3.95 | 6.32
 | Půdorys 5.NP | ZELEZOBETONOVÁ KCE | Betonářské práce | 0 | 0 | @452@ | 1852Slo0000010750 | m3 | Sloup | EXISTING | yes | 0.4 | 0.4 | 0.16 | 0.632 | 0.632 | 3.95 | 6.32
 | Půdorys 5.NP | ZELEZOBETONOVÁ KCE | Betonářské práce | 0 | 0 | @452@ | 1852Slo0000010746 | m3 | Sloup | EXISTING | yes | 0.4 | 0.4 | 0.16 | 0.632 | 0.632 | 3.95 | 6.32
 | Půdorys 5.NP | ZELEZOBETONOVÁ KCE | Betonářské práce | 0 | 0 | @452@ | 1852Slo0000010744 | m3 | Sloup | EXISTING | yes | 0.4 | 0.4 | 0.16 | 0.632 | 0.632 | 3.95 | 6.32
 | Půdorys 5.NP | ZELEZOBETONOVÁ KCE | Betonářské práce | 0 | 0 | @452@ | 1852Slo0000010740 | m3 | Sloup | EXISTING | yes | 0.4 | 0.4 | 0.16 | 0.632 | 0.632 | 3.95 | 6.32
 | Půdorys 5.NP | ZELEZOBETONOVÁ KCE | Betonářské práce | 0 | 0 | @452@ | 1852Slo0000010742 | m3 | Sloup | EXISTING | yes | 0.4 | 0.4 | 0.16 | 0.632 | 0.632 | 3.95 | 6.32
 | Půdorys 5.NP | ZELEZOBETONOVÁ KCE | Betonářské práce | 0 | 0 | @452@ | 1852Slo0000010748 | m3 | Sloup | EXISTING | yes | 0.4 | 0.4 | 0.16 | 0.632 | 0.632 | 3.95 | 6.32
 | Půdorys 5.NP | ZELEZOBETONOVÁ KCE | Betonářské práce | 0 | 0 | @452@ | 1852Slo0000010758 | m3 | Sloup | EXISTING | yes | 0.4 | 0.4 | 0.16 | 0.632 | 0.632 | 3.95 | 6.32
 | Půdorys 5.NP | ZELEZOBETONOVÁ KCE | Betonářské práce | 0 | 0 | @452@ | 1852Slo0000010727 | m3 | Sloup | EXISTING | yes | 0.4 | 0.4 | 0.16 | 0.632 | 0.632 | 3.95 | 6.32
 | Půdorys 5.NP | ZELEZOBETONOVÁ KCE | Betonářské práce | 0 | 0 | @452@ | 1852Slo0000010734 | m3 | Sloup | EXISTING | yes | 0.4 | 0.4 | 0.16 | 0.632 | 0.632 | 3.95 | 6.32
 | Půdorys 5.NP | ZELEZOBETONOVÁ KCE | Betonářské práce | 0 | 0 | @452@ | 1852Slo0000010764 | m3 | Sloup | EXISTING | yes | 0.4 | 0.4 | 0.16 | 0.632 | 0.632 | 3.95 | 6.32
 | Půdorys 5.NP | ZELEZOBETONOVÁ KCE | Betonářské práce | 0 | 0 | @452@ | 1852Slo0000010760 | m3 | Sloup | EXISTING | yes | 0.4 | 0.4 | 0.16 | 0.632 | 0.632 | 3.95 | 6.32
 | Půdorys 5.NP | ZELEZOBETONOVÁ KCE | Betonářské práce | 0 | 0 | @452@ | 1852Slo0798426090 | m3 | Sloup | EXISTING | yes | 0.4 | 0.4 | 0.16 | 0.632 | 0.632 | 3.95 | 6.32
 | Půdorys 5.NP | ZELEZOBETONOVÁ KCE | Betonářské práce | 0 | 0 | @452@ | 1852Slo0798426091 | m3 | Sloup | EXISTING | yes | 0.4 | 0.4 | 0.16 | 0.632 | 0.632 | 3.95 | 6.32
 | Půdorys 5.NP | ZELEZOBETONOVÁ KCE | Betonářské práce | 0 | 0 | @452@ | 1852Slo0000010680 | m3 | Sloup | EXISTING | yes | 0.4 | 0.4 | 0.16 | 0.632 | 0.632 | 3.95 | 6.32
 | Půdorys 5.NP | ZELEZOBETONOVÁ KCE | Betonářské práce | 0 | 0 | @452@ | 1852Slo0000010754 | m3 | Sloup | EXISTING | yes | 0.4 | 0.4 | 0.16 | 0.632 | 0.632 | 3.95 | 6.32
 | Půdorys 5.NP | ZELEZOBETONOVÁ KCE | Betonářské práce | 0 | 0 | @452@ | 1852Slo0000010756 | m3 | Sloup | EXISTING | yes | 0.4 | 0.4 | 0.16 | 0.632 | 0.632 | 3.95 | 6.32

# IfcCovering (314)
Name | In | PredefinedType | Material | Object Layer Attributes #1, Číslo_vrstvy | Object Layer Attributes #1, Tloušťka_vrstvy (m) | Object Layer Attributes #1, Tloušťka (m) = Object Layer Attributes #1, Vztažná_výška = Object Layer Attributes #1, Delta_výšky | Object Layer Attributes #1, Faktor | Object Layer Attributes #1, Allright_Stavebni_dil_ID | Object Layer Attributes #1, Jednotka | Object Layer Attributes #1, Název_objektu | Status | NetArea (m2) | Width (m) | Perimeter (m)
 | Půdorys 1.PP | CLADDING | KERAMICKÝ OBKLAD 0.015 m | 1 | 0.015 | 0 | 1 | 1364Spl0000007262/01 | m3 | Plocha stěny | NEW | 1.404 | 0.015 | NEMSOK - Object Layer Attributes #1, Kód prvku: OD01.02.0001; Object Layer Attributes #1, Práce: Obklady a dlažby; Object Layer Attributes #1, Materiál: KERAMICKÝ OBKLAD; Object Layer Attributes #1, Podlaží: 1.PP; Object Layer Attributes #1, Způsob položení: flexibilní tmel; Object Layer Attributes #1, Typ hydroizolace: bez; Qto_CoveringBaseQuantities - GrossArea: 1.404 m2
 | Půdorys 1.PP | CLADDING | KERAMICKÝ OBKLAD 0.015 m | 1 | 0.015 | 0 | 1 | 1364Spl0000007343/01 | m3 | Plocha stěny | NEW | 1.4 | 0.015 | NEMSOK - Object Layer Attributes #1, Kód prvku: OD01.02.0003; Object Layer Attributes #1, Práce: Obklady a dlažby; Object Layer Attributes #1, Materiál: KERAMICKÝ OBKLAD; Object Layer Attributes #1, Podlaží: 1.PP; Object Layer Attributes #1, Způsob položení: flexibilní tmel; Object Layer Attributes #1, Typ hydroizolace: bez; Qto_CoveringBaseQuantities - GrossArea: 1.4 m2
 | Půdorys 1.PP | CLADDING | KERAMICKÝ OBKLAD 0.015 m | 1 | 0.015 | 0 | 1 | 1364Spl0000007349/01 | m3 | Plocha stěny | NEW | 1.425 | 0.015 | NEMSOK - Object Layer Attributes #1, Kód prvku: OD01.02.0004; Object Layer Attributes #1, Práce: Obklady a dlažby; Object Layer Attributes #1, Materiál: KERAMICKÝ OBKLAD; Object Layer Attributes #1, Podlaží: 1.PP; Object Layer Attributes #1, Způsob položení: flexibilní tmel; Object Layer Attributes #1, Typ hydroizolace: bez; Qto_CoveringBaseQuantities - GrossArea: 1.425 m2
 | Půdorys 1.PP | CLADDING | KERAMICKÝ OBKLAD 0.015 m | 1 | 0.015 | 0 | 1 | 1364Spl0798477186/01 | m3 | Plocha stěny | NEW | 1.383 | 0.015 | NEMSOK - Object Layer Attributes #1, Kód prvku: OD01.02.0005; Object Layer Attributes #1, Práce: Obklady a dlažby; Object Layer Attributes #1, Materiál: KERAMICKÝ OBKLAD; Object Layer Attributes #1, Podlaží: 1.PP; Object Layer Attributes #1, Způsob položení: flexibilní tmel; Object Layer Attributes #1, Typ hydroizolace: bez; Qto_CoveringBaseQuantities - GrossArea: 1.383 m2
 | Půdorys 1.PP | CLADDING | KERAMICKÝ OBKLAD 0.015 m | 1 | 0.015 | 0 | 1 | 1364Spl0798495679/01 | m3 | Plocha stěny | NEW | 2.124 | 0.015 | NEMSOK - Object Layer Attributes #1, Kód prvku: OD01.02.0006; Object Layer Attributes #1, Práce: Obklady a dlažby; Object Layer Attributes #1, Materiál: KERAMICKÝ OBKLAD; Object Layer Attributes #1, Podlaží: 1.PP; Object Layer Attributes #1, Způsob položení: flexibilní tmel; Object Layer Attributes #1, Typ hydroizolace: bez; Qto_CoveringBaseQuantities - GrossArea: 2.124 m2
 | Půdorys 1.PP | CLADDING | KERAMICKÝ OBKLAD 0.015 m | 1 | 0.015 | 0 | 1 | 1364Spl0798495716/01 | m3 | Plocha stěny | NEW | 1.358 | 0.015 | NEMSOK - Object Layer Attributes #1, Kód prvku: OD01.02.0007; Object Layer Attributes #1, Práce: Obklady a dlažby; Object Layer Attributes #1, Materiál: KERAMICKÝ OBKLAD; Object Layer Attributes #1, Podlaží: 1.PP; Object Layer Attributes #1, Způsob položení: flexibilní tmel; Object Layer Attributes #1, Typ hydroizolace: bez; Qto_CoveringBaseQuantities - GrossArea: 1.358 m2
 | Půdorys 1.PP | CLADDING | KERAMICKÝ OBKLAD 0.015 m | 1 | 0.015 | 0 | 1 | 1364Spl0798495746/01 | m3 | Plocha stěny | NEW | 1.4 | 0.015 | NEMSOK - Object Layer Attributes #1, Kód prvku: OD01.02.0008; Object Layer Attributes #1, Práce: Obklady a dlažby; Object Layer Attributes #1, Materiál: KERAMICKÝ OBKLAD; Object Layer Attributes #1, Podlaží: 1.PP; Object Layer Attributes #1, Způsob položení: flexibilní tmel; Object Layer Attributes #1, Typ hydroizolace: bez; Qto_CoveringBaseQuantities - GrossArea: 1.4 m2
 | Půdorys 1.PP | CLADDING | KERAMICKÝ OBKLAD 0.015 m | 1 | 0.015 | 0 | 1 | 1364Spl0798500118/01 | m3 | Plocha stěny | NEW | 1.44 | 0.015 | NEMSOK - Object Layer Attributes #1, Kód prvku: OD01.02.0009; Object Layer Attributes #1, Práce: Obklady a dlažby; Object Layer Attributes #1, Materiál: KERAMICKÝ OBKLAD; Object Layer Attributes #1, Podlaží: 1.PP; Object Layer Attributes #1, Způsob položení: flexibilní tmel; Object Layer Attributes #1, Typ hydroizolace: bez; Qto_CoveringBaseQuantities - GrossArea: 1.44 m2
 | Půdorys 1.PP | CLADDING | KERAMICKÝ OBKLAD 0.015 m | 1 | 0.015 | 0 | 1 | 1364Spl0798505180/01 | m3 | Plocha stěny | NEW | 1.404 | 0.015 | NEMSOK - Object Layer Attributes #1, Kód prvku: OD01.02.0010; Object Layer Attributes #1, Práce: Obklady a dlažby; Object Layer Attributes #1, Materiál: KERAMICKÝ OBKLAD; Object Layer Attributes #1, Podlaží: 1.PP; Object Layer Attributes #1, Způsob položení: flexibilní tmel; Object Layer Attributes #1, Typ hydroizolace: bez; Qto_CoveringBaseQuantities - GrossArea: 1.404 m2
 | Půdorys 1.PP | CLADDING | KERAMICKÝ OBKLAD 0.015 m | 1 | 0.015 | 0 | 1 | 1364Spl0798505204/01 | m3 | Plocha stěny | NEW | 1.404 | 0.015 | NEMSOK - Object Layer Attributes #1, Kód prvku: OD01.02.0011; Object Layer Attributes #1, Práce: Obklady a dlažby; Object Layer Attributes #1, Materiál: KERAMICKÝ OBKLAD; Object Layer Attributes #1, Podlaží: 1.PP; Object Layer Attributes #1, Způsob položení: flexibilní tmel; Object Layer Attributes #1, Typ hydroizolace: bez; Qto_CoveringBaseQuantities - GrossArea: 1.404 m2
 | Půdorys 1.PP | CLADDING | KERAMICKÝ OBKLAD 0.015 m | 1 | 0.015 | 0 | 1 | 1364Spl0798505251/01 | m3 | Plocha stěny | NEW | 1.404 | 0.015 | NEMSOK - Object Layer Attributes #1, Kód prvku: OD01.02.0012; Object Layer Attributes #1, Práce: Obklady a dlažby; Object Layer Attributes #1, Materiál: KERAMICKÝ OBKLAD; Object Layer Attributes #1, Podlaží: 1.PP; Object Layer Attributes #1, Způsob položení: flexibilní tmel; Object Layer Attributes #1, Typ hydroizolace: bez; Qto_CoveringBaseQuantities - GrossArea: 1.404 m2
 | Půdorys 1.PP | CLADDING | KERAMICKÝ OBKLAD 0.015 m | 1 | 0.015 | 0 | 1 | 1364Spl0798505273/01 | m3 | Plocha stěny | NEW | 1.404 | 0.015 | NEMSOK - Object Layer Attributes #1, Kód prvku: OD01.02.0013; Object Layer Attributes #1, Práce: Obklady a dlažby; Object Layer Attributes #1, Materiál: KERAMICKÝ OBKLAD; Object Layer Attributes #1, Podlaží: 1.PP; Object Layer Attributes #1, Způsob položení: flexibilní tmel; Object Layer Attributes #1, Typ hydroizolace: bez; Qto_CoveringBaseQuantities - GrossArea: 1.404 m2
 | Půdorys 1.PP | CLADDING | KERAMICKÝ OBKLAD 0.015 m | 1 | 0.015 | 0 | 1 | 1364Spl0798529933/01 | m3 | Plocha stěny | NEW | 0.84 | 0.015 | NEMSOK - Object Layer Attributes #1, Kód prvku: OD01.02.0014; Object Layer Attributes #1, Práce: Obklady a dlažby; Object Layer Attributes #1, Materiál: KERAMICKÝ OBKLAD; Object Layer Attributes #1, Podlaží: 1.PP; Object Layer Attributes #1, Způsob položení: flexibilní tmel; Object Layer Attributes #1, Typ hydroizolace: bez; Qto_CoveringBaseQuantities - GrossArea: 0.84 m2
 | Půdorys 1.PP | CLADDING | KERAMICKÝ OBKLAD 0.015 m | 1 | 0.015 | 0 | 1 | 1364Spl0000007302/01 | m3 | Plocha stěny | NEW | 1.4 | 0.015 | NEMSOK - Object Layer Attributes #1, Kód prvku: OD01.02.0002; Object Layer Attributes #1, Práce: Obklady a dlažby; Object Layer Attributes #1, Materiál: KERAMICKÝ OBKLAD; Object Layer Attributes #1, Podlaží: 1.PP; Object Layer Attributes #1, Způsob položení: flexibilní tmel; Object Layer Attributes #1, Typ hydroizolace: bez; Qto_CoveringBaseQuantities - GrossArea: 1.4 m2
 | Půdorys 1.PP | CLADDING | KERAMICKÝ OBKLAD 0.015 m | 1 | 0.015 | 0 | 1 | 1364Spl0798561814/01 | m3 | Plocha stěny | NEW | 3.08 | 0.015 | NEMSOK - Object Layer Attributes #1, Kód prvku: OD01.02.0015; Object Layer Attributes #1, Práce: Obklady a dlažby; Object Layer Attributes #1, Materiál: KERAMICKÝ OBKLAD; Object Layer Attributes #1, Podlaží: 1.PP; Object Layer Attributes #1, Způsob položení: flexibilní tmel; Object Layer Attributes #1, Typ hydroizolace: bez; Qto_CoveringBaseQuantities - GrossArea: 3.08 m2
 | Půdorys 1.PP | FLOORING | KERAMICKÝ OBKLAD 0.015 m | 1 | 0.015 |  |  | 1364Ppl0000010720/01 | m3 | Plocha podlahy | NEW | 0 | 0.015 | 0 | NEMSOK - Object Layer Attributes #1, Kód prvku: OD01.02.0001; Object Layer Attributes #1, Práce: Obklady a dlažby; Object Layer Attributes #1, Materiál: KERAMICKÝ OBKLAD; Object Layer Attributes #1, Podlaží: 1.PP; Object Layer Attributes #1, Způsob položení: flexibilní tmel; Object Layer Attributes #1, Typ hydroizolace: bez
 | Půdorys 1.PP | CLADDING | KERAMICKÝ OBKLAD 0.015 m | 1 | 0.015 |  |  | 1364Spl0000010719/01 | m3 | Plocha stěny | NEW | 0 | 0.015 | NEMSOK - Object Layer Attributes #1, Kód prvku: OD01.02.0002; Object Layer Attributes #1, Práce: Obklady a dlažby; Object Layer Attributes #1, Materiál: KERAMICKÝ OBKLAD; Object Layer Attributes #1, Podlaží: 1.PP; Object Layer Attributes #1, Způsob položení: flexibilní tmel; Object Layer Attributes #1, Typ hydroizolace: bez; Qto_CoveringBaseQuantities - GrossArea: 0 m2
 | Půdorys 1.PP | FLOORING | SANACE BETONU 0.003 m | 1 | 0.003 | 0 | 1 | 1369Ppl0000001607/01 | m3 | Plocha podlahy | NEW | 2.8 | 0.003 | 7.6 | NEMSOK - Object Layer Attributes #1, Kód prvku: MB05.02.1001; Object Layer Attributes #1, Práce: Potěry a stěrky; Object Layer Attributes #1, Materiál: SANACE BETONU; Object Layer Attributes #1, Podlaží: 1.PP; Object Layer Attributes #1, Způsob provedení: ruční
 | Půdorys 1.PP | FLOORING | SANACE BETONU 0.003 m | 1 | 0.003 | 0 | 1 | 1369Ppl0000001609/01 | m3 | Plocha podlahy | NEW | 2.8 | 0.003 | 7.6 | NEMSOK - Object Layer Attributes #1, Kód prvku: MB05.02.1001; Object Layer Attributes #1, Práce: Potěry a stěrky; Object Layer Attributes #1, Materiál: SANACE BETONU; Object Layer Attributes #1, Podlaží: 1.PP; Object Layer Attributes #1, Způsob provedení: ruční
 | Půdorys 1.PP | FLOORING | SANACE BETONU 0.003 m | 1 | 0.003 | 0 | 1 | 1369Ppl0000001611/01 | m3 | Plocha podlahy | NEW | 2.8 | 0.003 | 7.6 | NEMSOK - Object Layer Attributes #1, Kód prvku: MB05.02.1001; Object Layer Attributes #1, Práce: Potěry a stěrky; Object Layer Attributes #1, Materiál: SANACE BETONU; Object Layer Attributes #1, Podlaží: 1.PP; Object Layer Attributes #1, Způsob provedení: ruční
 | Půdorys 1.PP | FLOORING | SANACE BETONU 0.003 m | 1 | 0.003 | 0 | 1 | 1369Ppl0000001613/01 | m3 | Plocha podlahy | NEW | 6.111 | 0.003 | 14.28 | NEMSOK - Object Layer Attributes #1, Kód prvku: MB05.02.1001; Object Layer Attributes #1, Práce: Potěry a stěrky; Object Layer Attributes #1, Materiál: SANACE BETONU; Object Layer Attributes #1, Podlaží: 1.PP; Object Layer Attributes #1, Způsob provedení: ruční
 | Půdorys 1.PP | FLOORING | SANACE BETONU 0.003 m | 1 | 0.003 | 0 | 1 | 1369Ppl0000001615/01 | m3 | Plocha podlahy | NEW | 2.8 | 0.003 | 7.6 | NEMSOK - Object Layer Attributes #1, Kód prvku: MB05.02.1001; Object Layer Attributes #1, Práce: Potěry a stěrky; Object Layer Attributes #1, Materiál: SANACE BETONU; Object Layer Attributes #1, Podlaží: 1.PP; Object Layer Attributes #1, Způsob provedení: ruční
 | Půdorys 1.PP | FLOORING | SANACE BETONU 0.003 m | 1 | 0.003 | 0 | 1 | 1369Ppl0000001617/01 | m3 | Plocha podlahy | NEW | 2.8 | 0.003 | 7.6 | NEMSOK - Object Layer Attributes #1, Kód prvku: MB05.02.1001; Object Layer Attributes #1, Práce: Potěry a stěrky; Object Layer Attributes #1, Materiál: SANACE BETONU; Object Layer Attributes #1, Podlaží: 1.PP; Object Layer Attributes #1, Způsob provedení: ruční
 | Půdorys 1.PP | FLOORING | SANACE BETONU 0.003 m | 1 | 0.003 | 0 | 1 | 1369Ppl0000001619/01 | m3 | Plocha podlahy | NEW | 2.8 | 0.003 | 7.6 | NEMSOK - Object Layer Attributes #1, Kód prvku: MB05.02.1001; Object Layer Attributes #1, Práce: Potěry a stěrky; Object Layer Attributes #1, Materiál: SANACE BETONU; Object Layer Attributes #1, Podlaží: 1.PP; Object Layer Attributes #1, Způsob provedení: ruční
 | Půdorys 1.PP | FLOORING | SANACE BETONU 0.003 m | 1 | 0.003 | 0 | 1 | 1369Ppl0000001621/01 | m3 | Plocha podlahy | NEW | 2.8 | 0.003 | 7.6 | NEMSOK - Object Layer Attributes #1, Kód prvku: MB05.02.1001; Object Layer Attributes #1, Práce: Potěry a stěrky; Object Layer Attributes #1, Materiál: SANACE BETONU; Object Layer Attributes #1, Podlaží: 1.PP; Object Layer Attributes #1, Způsob provedení: ruční
 | Půdorys 1.PP | FLOORING | SANACE BETONU 0.003 m | 1 | 0.003 | 0 | 1 | 1369Ppl0000001623/01 | m3 | Plocha podlahy | NEW | 2.8 | 0.003 | 7.6 | NEMSOK - Object Layer Attributes #1, Kód prvku: MB05.02.1001; Object Layer Attributes #1, Práce: Potěry a stěrky; Object Layer Attributes #1, Materiál: SANACE BETONU; Object Layer Attributes #1, Podlaží: 1.PP; Object Layer Attributes #1, Způsob provedení: ruční
 | Půdorys 1.PP | FLOORING | SANACE BETONU 0.003 m | 1 | 0.003 | 0 | 1 | 1369Ppl0000001625/01 | m3 | Plocha podlahy | NEW | 3.225 | 0.003 | 8.45 | NEMSOK - Object Layer Attributes #1, Kód prvku: MB05.02.1001; Object Layer Attributes #1, Práce: Potěry a stěrky; Object Layer Attributes #1, Materiál: SANACE BETONU; Object Layer Attributes #1, Podlaží: 1.PP; Object Layer Attributes #1, Způsob provedení: ruční
 | Půdorys 1.PP | FLOORING | SANACE BETONU 0.003 m | 1 | 0.003 | 0 | 1 | 1369Ppl0000001721/01 | m3 | Plocha podlahy | NEW | 5.552 | 0.003 | 55.92 | NEMSOK - Object Layer Attributes #1, Kód prvku: MB05.02.1001; Object Layer Attributes #1, Práce: Potěry a stěrky; Object Layer Attributes #1, Materiál: SANACE BETONU; Object Layer Attributes #1, Podlaží: 1.PP; Object Layer Attributes #1, Způsob provedení: ruční
 | Půdorys 1.PP | FLOORING | SANACE BETONU 0.003 m | 1 | 0.003 | 0 | 1 | 1369Ppl0000001728/01 | m3 | Plocha podlahy | NEW | 0.063 | 0.003 | 1 | NEMSOK - Object Layer Attributes #1, Kód prvku: MB05.02.1001; Object Layer Attributes #1, Práce: Potěry a stěrky; Object Layer Attributes #1, Materiál: SANACE BETONU; Object Layer Attributes #1, Podlaží: 1.PP; Object Layer Attributes #1, Způsob provedení: ruční
 | Půdorys 1.PP | FLOORING | SANACE BETONU 0.003 m | 1 | 0.003 | 0 | 1 | 1369Ppl0000001747/01 | m3 | Plocha podlahy | NEW | 3.585 | 0.003 | 36.25 | NEMSOK - Object Layer Attributes #1, Kód prvku: MB05.02.1001; Object Layer Attributes #1, Práce: Potěry a stěrky; Object Layer Attributes #1, Materiál: SANACE BETONU; Object Layer Attributes #1, Podlaží: 1.PP; Object Layer Attributes #1, Způsob provedení: ruční
 | -1.34 | FLOORING | layer 0.095 m, PŘÍRODNÍ LINOLEUM 0.005 m | 1 | 0.095 | 0 | 1 | 1369Ppl0000000004/01 | m3 | Plocha podlahy | NEW | 76.24 | 0.1 | 0 | NEMSOK - Object Layer Attributes #2, Status: Nový; Object Layer Attributes #2, Kód prvku: PD06.02.0001; Object Layer Attributes #2, Práce: Povlakové podlahy; Object Layer Attributes #2, Číslo_vrstvy: 2; Object Layer Attributes #2, Tloušťka_vrstvy: 0.005 m; Object Layer Attributes #2, Tloušťka: 0 m; Object Layer Attributes #2, Faktor: 1; Object Layer Attributes #2, Označení: I.P1; Object Layer Attributes #2, Materiál: PŘÍRODNÍ LINOLEUM; Object Layer Attributes #2, Vztažná_výška: 0; Object Layer Attributes #2, Delta_výšky: 0; Object Layer Attributes #2, Podlaží: 1.PP; Object Layer Attributes #2, Číslo místnosti: -1.34; Object Layer Attributes #2, Plošná únosnost: 5; Object Layer Attributes #2, Allright_Stavebni_dil_ID: 1369Ppl0000000004/02; Object Layer Attributes #2, Jednotka: m3; Object Layer Attributes #2, Název_objektu: Plocha podlahy
 | -1.34 | SKIRTINGBOARD | FABION |  |  |  |  |  |  |  | NEW | NEMSOK - Kód prvku: PD00.02.0000; Práce: Povlakové podlahy; Faktor: 1; Materiál: FABION; Vztažná_výška: 0; Delta_výšky: 0; Allright_Stavebni_dil_ID: 1369Liš0000001429; Jednotka: m; Název_objektu: Lišta
 | -1.34 | CEILING | RASTR 1 0.03 m | 1 | 0.03 | 0 | 1 | 1369Dpl0000000003/01 | m3 | Plocha stropu | NEW | 76.24 | 0.03 | 0 | NEMSOK - Object Layer Attributes #1, Kód prvku: PH03.02.1001; Object Layer Attributes #1, Práce: Suché stavební práce; Object Layer Attributes #1, Materiál: RASTR 1; Object Layer Attributes #1, Výška svěšení: 0.65 m; Object Layer Attributes #1, Únosnost bodová: 0.5 kg; Pset_CoveringCommon - Flammability: bez požadavku
 | -1.35 | FLOORING | layer 0.095 m, ELEKTROSTATICKÝ VINYL 0.005 m | 1 | 0.095 | 0 | 1 | 1369Ppl0000000015/01 | m3 | Plocha podlahy | NEW | 16.165 | 0.1 | 0 | NEMSOK - Object Layer Attributes #2, Status: Nový; Object Layer Attributes #2, Kód prvku: PD06.02.1001; Object Layer Attributes #2, Práce: Povlakové podlahy; Object Layer Attributes #2, Číslo_vrstvy: 2; Object Layer Attributes #2, Tloušťka_vrstvy: 0.005 m; Object Layer Attributes #2, Tloušťka: 0 m; Object Layer Attributes #2, Faktor: 1; Object Layer Attributes #2, Označení: I.P2; Object Layer Attributes #2, Materiál: ELEKTROSTATICKÝ VINYL; Object Layer Attributes #2, Vztažná_výška: 0; Object Layer Attributes #2, Delta_výšky: 0; Object Layer Attributes #2, Podlaží: 1.PP; Object Layer Attributes #2, Číslo místnosti: -1.35; Object Layer Attributes #2, Plošná únosnost: 5; Object Layer Attributes #2, Allright_Stavebni_dil_ID: 1369Ppl0000000015/02; Object Layer Attributes #2, Jednotka: m3; Object Layer Attributes #2, Název_objektu: Plocha podlahy
 | -1.35 | SKIRTINGBOARD | FABION |  |  |  |  |  |  |  | NEW | NEMSOK - Kód prvku: PD00.02.0000; Práce: Povlakové podlahy; Faktor: 1; Materiál: FABION; Vztažná_výška: 0; Delta_výšky: 0; Allright_Stavebni_dil_ID: 1369Liš0000001425; Jednotka: m; Název_objektu: Lišta
 | -1.35 | CEILING | RASTR 3 0.03 m | 1 | 0.03 | 0 | 1 | 1369Dpl0000000014/01 | m3 | Plocha stropu | NEW | 16.165 | 0.03 | 0 | NEMSOK - Object Layer Attributes #1, Kód prvku: PH03.02.3001; Object Layer Attributes #1, Práce: Suché stavební práce; Object Layer Attributes #1, Materiál: RASTR 3; Object Layer Attributes #1, Výška svěšení: 0.35 m; Object Layer Attributes #1, Únosnost bodová: 0.5 kg; Pset_CoveringCommon - Flammability: bez požadavku
 | -1.39 | FLOORING | layer 0.095 m, ELEKTROSTATICKÝ VINYL 0.005 m | 1 | 0.095 | 0 | 1 | 1369Ppl0000000057/01 | m3 | Plocha podlahy | NEW | 15.486 | 0.1 | 0 | NEMSOK - Object Layer Attributes #2, Status: Nový; Object Layer Attributes #2, Kód prvku: PD06.02.1001; Object Layer Attributes #2, Práce: Povlakové podlahy; Object Layer Attributes #2, Číslo_vrstvy: 2; Object Layer Attributes #2, Tloušťka_vrstvy: 0.005 m; Object Layer Attributes #2, Tloušťka: 0 m; Object Layer Attributes #2, Faktor: 1; Object Layer Attributes #2, Označení: I.P2; Object Layer Attributes #2, Materiál: ELEKTROSTATICKÝ VINYL; Object Layer Attributes #2, Vztažná_výška: 0; Object Layer Attributes #2, Delta_výšky: 0; Object Layer Attributes #2, Podlaží: 1.PP; Object Layer Attributes #2, Číslo místnosti: -1.39; Object Layer Attributes #2, Plošná únosnost: 5; Object Layer Attributes #2, Allright_Stavebni_dil_ID: 1369Ppl0000000057/02; Object Layer Attributes #2, Jednotka: m3; Object Layer Attributes #2, Název_objektu: Plocha podlahy
 | -1.39 | SKIRTINGBOARD | FABION |  |  |  |  |  |  |  | NEW | NEMSOK - Kód prvku: PD00.02.0000; Práce: Povlakové podlahy; Faktor: 1; Materiál: FABION; Vztažná_výška: 0; Delta_výšky: 0; Allright_Stavebni_dil_ID: 1369Liš0000001430; Jednotka: m; Název_objektu: Lišta
 | -1.39 | CEILING | RASTR 3 0.03 m | 1 | 0.03 | 0 | 1 | 1369Dpl0000000056/01 | m3 | Plocha stropu | NEW | 15.486 | 0.03 | 0 | NEMSOK - Object Layer Attributes #1, Kód prvku: PH03.02.3001; Object Layer Attributes #1, Práce: Suché stavební práce; Object Layer Attributes #1, Materiál: RASTR 3; Object Layer Attributes #1, Výška svěšení: 0.35 m; Object Layer Attributes #1, Únosnost bodová: 0.5 kg; Pset_CoveringCommon - Flammability: bez požadavku
 | -1.46 | FLOORING | layer 0.095 m, ELEKTROSTATICKÝ VINYL 0.005 m | 1 | 0.095 | 0 | 1 | 1369Ppl0000000142/01 | m3 | Plocha podlahy | NEW | 17.289 | 0.1 | 0 | NEMSOK - Object Layer Attributes #2, Status: Nový; Object Layer Attributes #2, Kód prvku: PD06.02.1001; Object Layer Attributes #2, Práce: Povlakové podlahy; Object Layer Attributes #2, Číslo_vrstvy: 2; Object Layer Attributes #2, Tloušťka_vrstvy: 0.005 m; Object Layer Attributes #2, Tloušťka: 0 m; Object Layer Attributes #2, Faktor: 1; Object Layer Attributes #2, Označení: I.P2; Object Layer Attributes #2, Materiál: ELEKTROSTATICKÝ VINYL; Object Layer Attributes #2, Vztažná_výška: 0; Object Layer Attributes #2, Delta_výšky: 0; Object Layer Attributes #2, Podlaží: 1.PP; Object Layer Attributes #2, Číslo místnosti: -1.46; Object Layer Attributes #2, Plošná únosnost: 5; Object Layer Attributes #2, Allright_Stavebni_dil_ID: 1369Ppl0000000142/02; Object Layer Attributes #2, Jednotka: m3; Object Layer Attributes #2, Název_objektu: Plocha podlahy
 | -1.46 | SKIRTINGBOARD | FABION |  |  |  |  |  |  |  | NEW | NEMSOK - Kód prvku: PD00.02.0000; Práce: Povlakové podlahy; Faktor: 1; Materiál: FABION; Vztažná_výška: 0; Delta_výšky: 0; Allright_Stavebni_dil_ID: 1369Liš0000001431; Jednotka: m; Název_objektu: Lišta
 | -1.46 | CEILING | RASTR 3 0.03 m | 1 | 0.03 | 0 | 1 | 1369Dpl0000000141/01 | m3 | Plocha stropu | NEW | 17.289 | 0.03 | 0 | NEMSOK - Object Layer Attributes #1, Kód prvku: PH03.02.3001; Object Layer Attributes #1, Práce: Suché stavební práce; Object Layer Attributes #1, Materiál: RASTR 3; Object Layer Attributes #1, Výška svěšení: 0.35 m; Object Layer Attributes #1, Únosnost bodová: 0.5 kg; Pset_CoveringCommon - Flammability: bez požadavku
 | -1.47 | FLOORING | layer 0.085 m, KERAMICKÁ DLAŽBA 0.015 m | 1 | 0.085 | 0 | 1 | 1369Ppl0000000151/01 | m3 | Plocha podlahy | NEW | 1.77 | 0.1 | 0 | NEMSOK - Object Layer Attributes #2, Status: Nový; Object Layer Attributes #2, Kód prvku: PD01.02.0001; Object Layer Attributes #2, Práce: Obklady a dlažby; Object Layer Attributes #2, Číslo_vrstvy: 2; Object Layer Attributes #2, Tloušťka_vrstvy: 0.015 m; Object Layer Attributes #2, Tloušťka: 0 m; Object Layer Attributes #2, Faktor: 1; Object Layer Attributes #2, Označení: I.P3; Object Layer Attributes #2, Materiál: KERAMICKÁ DLAŽBA; Object Layer Attributes #2, Vztažná_výška: 0; Object Layer Attributes #2, Delta_výšky: 0; Object Layer Attributes #2, Podlaží: 1.PP; Object Layer Attributes #2, Číslo místnosti: -1.47; Object Layer Attributes #2, Plošná únosnost: 5; Object Layer Attributes #2, Allright_Stavebni_dil_ID: 1369Ppl0000000151/02; Object Layer Attributes #2, Jednotka: m3; Object Layer Attributes #2, Název_objektu: Plocha podlahy
 | -1.47 | CEILING | RASTR 2 0.03 m | 1 | 0.03 | 0 | 1 | 1369Dpl0000000150/01 | m3 | Plocha stropu | NEW | 1.77 | 0.03 | 0 | NEMSOK - Object Layer Attributes #1, Kód prvku: PH03.02.2001; Object Layer Attributes #1, Práce: Suché stavební práce; Object Layer Attributes #1, Materiál: RASTR 2; Object Layer Attributes #1, Výška svěšení: 0.35 m; Object Layer Attributes #1, Únosnost bodová: 0.5 kg; Pset_CoveringCommon - Flammability: bez požadavku
 | -1.48 | FLOORING | layer 0.085 m, KERAMICKÁ DLAŽBA 0.015 m | 1 | 0.085 | 0 | 1 | 1369Ppl0000000160/01 | m3 | Plocha podlahy | NEW | 1.61 | 0.1 | 0 | NEMSOK - Object Layer Attributes #2, Status: Nový; Object Layer Attributes #2, Kód prvku: PD01.02.0001; Object Layer Attributes #2, Práce: Obklady a dlažby; Object Layer Attributes #2, Číslo_vrstvy: 2; Object Layer Attributes #2, Tloušťka_vrstvy: 0.015 m; Object Layer Attributes #2, Tloušťka: 0 m; Object Layer Attributes #2, Faktor: 1; Object Layer Attributes #2, Označení: I.P3; Object Layer Attributes #2, Materiál: KERAMICKÁ DLAŽBA; Object Layer Attributes #2, Vztažná_výška: 0; Object Layer Attributes #2, Delta_výšky: 0; Object Layer Attributes #2, Podlaží: 1.PP; Object Layer Attributes #2, Číslo místnosti: -1.48; Object Layer Attributes #2, Plošná únosnost: 5; Object Layer Attributes #2, Allright_Stavebni_dil_ID: 1369Ppl0000000160/02; Object Layer Attributes #2, Jednotka: m3; Object Layer Attributes #2, Název_objektu: Plocha podlahy
 | -1.48 | CEILING | RASTR 2 0.03 m | 1 | 0.03 | 0 | 1 | 1369Dpl0000000159/01 | m3 | Plocha stropu | NEW | 1.61 | 0.03 | 0 | NEMSOK - Object Layer Attributes #1, Kód prvku: PH03.02.2001; Object Layer Attributes #1, Práce: Suché stavební práce; Object Layer Attributes #1, Materiál: RASTR 2; Object Layer Attributes #1, Výška svěšení: 0.35 m; Object Layer Attributes #1, Únosnost bodová: 0.5 kg; Pset_CoveringCommon - Flammability: bez požadavku
 | -1.49 | FLOORING | layer 0.095 m, ELEKTROSTATICKÝ VINYL 0.005 m | 1 | 0.095 | 0 | 1 | 1369Ppl0000000171/01 | m3 | Plocha podlahy | NEW | 20.669 | 0.1 | 0 | NEMSOK - Object Layer Attributes #2, Status: Nový; Object Layer Attributes #2, Kód prvku: PD06.02.1001; Object Layer Attributes #2, Práce: Povlakové podlahy; Object Layer Attributes #2, Číslo_vrstvy: 2; Object Layer Attributes #2, Tloušťka_vrstvy: 0.005 m; Object Layer Attributes #2, Tloušťka: 0 m; Object Layer Attributes #2, Faktor: 1; Object Layer Attributes #2, Označení: I.P2; Object Layer Attributes #2, Materiál: ELEKTROSTATICKÝ VINYL; Object Layer Attributes #2, Vztažná_výška: 0; Object Layer Attributes #2, Delta_výšky: 0; Object Layer Attributes #2, Podlaží: 1.PP; Object Layer Attributes #2, Číslo místnosti: -1.49; Object Layer Attributes #2, Plošná únosnost: 5; Object Layer Attributes #2, Allright_Stavebni_dil_ID: 1369Ppl0000000171/02; Object Layer Attributes #2, Jednotka: m3; Object Layer Attributes #2, Název_objektu: Plocha podlahy
 | -1.49 | SKIRTINGBOARD | FABION |  |  |  |  |  |  |  | NEW | NEMSOK - Kód prvku: PD00.02.0000; Práce: Povlakové podlahy; Faktor: 1; Materiál: FABION; Vztažná_výška: 0; Delta_výšky: 0; Allright_Stavebni_dil_ID: 1369Liš0000001432; Jednotka: m; Název_objektu: Lišta
 | -1.49 | CEILING | RASTR 3 0.03 m | 1 | 0.03 | 0 | 1 | 1369Dpl0000000170/01 | m3 | Plocha stropu | NEW | 20.669 | 0.03 | 0 | NEMSOK - Object Layer Attributes #1, Kód prvku: PH03.02.3001; Object Layer Attributes #1, Práce: Suché stavební práce; Object Layer Attributes #1, Materiál: RASTR 3; Object Layer Attributes #1, Výška svěšení: 0.35 m; Object Layer Attributes #1, Únosnost bodová: 0.5 kg; Pset_CoveringCommon - Flammability: bez požadavku
 | -1.50 | FLOORING | layer 0.095 m, ELEKTROSTATICKÝ VINYL 0.005 m | 1 | 0.095 | 0 | 1 | 1369Ppl0000000180/01 | m3 | Plocha podlahy | NEW | 20.711 | 0.1 | 0 | NEMSOK - Object Layer Attributes #2, Status: Nový; Object Layer Attributes #2, Kód prvku: PD06.02.1001; Object Layer Attributes #2, Práce: Povlakové podlahy; Object Layer Attributes #2, Číslo_vrstvy: 2; Object Layer Attributes #2, Tloušťka_vrstvy: 0.005 m; Object Layer Attributes #2, Tloušťka: 0 m; Object Layer Attributes #2, Faktor: 1; Object Layer Attributes #2, Označení: I.P13; Object Layer Attributes #2, Materiál: ELEKTROSTATICKÝ VINYL; Object Layer Attributes #2, Vztažná_výška: 0; Object Layer Attributes #2, Delta_výšky: 0; Object Layer Attributes #2, Podlaží: 1.PP; Object Layer Attributes #2, Číslo místnosti: -1.50; Object Layer Attributes #2, Plošná únosnost: 5; Object Layer Attributes #2, Allright_Stavebni_dil_ID: 1369Ppl0000000180/02; Object Layer Attributes #2, Jednotka: m3; Object Layer Attributes #2, Název_objektu: Plocha podlahy
 | -1.50 | CEILING | BARYTOVÁ OMÍTKA 0.015 m, RASTR 3 0.03 m | 1 | 0.015 | 0 | 1 | 1369Dpl0000000179/01 | m3 | Plocha stropu | NEW | 20.711 | 0.045 | 0 | NEMSOK - Object Layer Attributes #1, Kód prvku: OM07.02.1001; Object Layer Attributes #1, Práce: Omítky a štuky; Object Layer Attributes #1, Materiál: BARYTOVÁ OMÍTKA; Object Layer Attributes #1, Způsob provedení: ruční; Object Layer Attributes #2, Status: Nový; Object Layer Attributes #2, Kód prvku: PH03.02.3001; Object Layer Attributes #2, Práce: Suché stavební práce; Object Layer Attributes #2, Číslo_vrstvy: 2; Object Layer Attributes #2, Tloušťka_vrstvy: 0.03 m; Object Layer Attributes #2, Tloušťka: 0 m; Object Layer Attributes #2, Faktor: 1; Object Layer Attributes #2, Materiál: RASTR 3; Object Layer Attributes #2, Vztažná_výška: 0; Object Layer Attributes #2, Delta_výšky: 0; Object Layer Attributes #2, Allright_Stavebni_dil_ID: 1369Dpl0000000179/02; Object Layer Attributes #2, Jednotka: m3; Object Layer Attributes #2, Název_objektu: Plocha stropu; Object Layer Attributes #2, Požární odolnost: bez požadavku; Object Layer Attributes #2, Výška svěšení: 0.35 m; Object Layer Attributes #2, Únosnost bodová: 0.5 kg
 | -1.50 | SKIRTINGBOARD | FABION |  |  |  |  |  |  |  | NEW | NEMSOK - Kód prvku: PD00.02.0000; Práce: Povlakové podlahy; Faktor: 1; Materiál: FABION; Vztažná_výška: 0; Delta_výšky: 0; Allright_Stavebni_dil_ID: 1369Liš0000001433; Jednotka: m; Název_objektu: Lišta
 | -1.51 | FLOORING | layer 0.095 m, ELEKTROSTATICKÝ VINYL 0.005 m | 1 | 0.095 | 0 | 1 | 1369Ppl0000000191/01 | m3 | Plocha podlahy | NEW | 17.4 | 0.1 | 0 | NEMSOK - Object Layer Attributes #2, Status: Nový; Object Layer Attributes #2, Kód prvku: PD06.02.1001; Object Layer Attributes #2, Práce: Povlakové podlahy; Object Layer Attributes #2, Číslo_vrstvy: 2; Object Layer Attributes #2, Tloušťka_vrstvy: 0.005 m; Object Layer Attributes #2, Tloušťka: 0 m; Object Layer Attributes #2, Faktor: 1; Object Layer Attributes #2, Označení: I.P2; Object Layer Attributes #2, Materiál: ELEKTROSTATICKÝ VINYL; Object Layer Attributes #2, Vztažná_výška: 0; Object Layer Attributes #2, Delta_výšky: 0; Object Layer Attributes #2, Podlaží: 1.PP; Object Layer Attributes #2, Číslo místnosti: -1.51; Object Layer Attributes #2, Plošná únosnost: 5; Object Layer Attributes #2, Allright_Stavebni_dil_ID: 1369Ppl0000000191/02; Object Layer Attributes #2, Jednotka: m3; Object Layer Attributes #2, Název_objektu: Plocha podlahy
 | -1.51 | SKIRTINGBOARD | FABION |  |  |  |  |  |  |  | NEW | NEMSOK - Kód prvku: PD00.02.0000; Práce: Povlakové podlahy; Faktor: 1; Materiál: FABION; Vztažná_výška: 0; Delta_výšky: 0; Allright_Stavebni_dil_ID: 1369Liš0000001434; Jednotka: m; Název_objektu: Lišta
 | -1.51 | CEILING | RASTR 3 0.03 m | 1 | 0.03 | 0 | 1 | 1369Dpl0000000190/01 | m3 | Plocha stropu | NEW | 17.4 | 0.03 | 0 | NEMSOK - Object Layer Attributes #1, Kód prvku: PH03.02.3001; Object Layer Attributes #1, Práce: Suché stavební práce; Object Layer Attributes #1, Materiál: RASTR 3; Object Layer Attributes #1, Výška svěšení: 0.35 m; Object Layer Attributes #1, Únosnost bodová: 0.5 kg; Pset_CoveringCommon - Flammability: bez požadavku
 | -1.52 | FLOORING | layer 0.095 m, ELEKTROSTATICKÝ VINYL 0.005 m | 1 | 0.095 | 0 | 1 | 1369Ppl0000000200/01 | m3 | Plocha podlahy | NEW | 17.27 | 0.1 | 0 | NEMSOK - Object Layer Attributes #2, Status: Nový; Object Layer Attributes #2, Kód prvku: PD06.02.1001; Object Layer Attributes #2, Práce: Povlakové podlahy; Object Layer Attributes #2, Číslo_vrstvy: 2; Object Layer Attributes #2, Tloušťka_vrstvy: 0.005 m; Object Layer Attributes #2, Tloušťka: 0 m; Object Layer Attributes #2, Faktor: 1; Object Layer Attributes #2, Označení: I.P2; Object Layer Attributes #2, Materiál: ELEKTROSTATICKÝ VINYL; Object Layer Attributes #2, Vztažná_výška: 0; Object Layer Attributes #2, Delta_výšky: 0; Object Layer Attributes #2, Podlaží: 1.PP; Object Layer Attributes #2, Číslo místnosti: -1.52; Object Layer Attributes #2, Plošná únosnost: 5; Object Layer Attributes #2, Allright_Stavebni_dil_ID: 1369Ppl0000000200/02; Object Layer Attributes #2, Jednotka: m3; Object Layer Attributes #2, Název_objektu: Plocha podlahy
 | -1.52 | SKIRTINGBOARD | FABION |  |  |  |  |  |  |  | NEW | NEMSOK - Kód prvku: PD00.02.0000; Práce: Povlakové podlahy; Faktor: 1; Materiál: FABION; Vztažná_výška: 0; Delta_výšky: 0; Allright_Stavebni_dil_ID: 1369Liš0000001435; Jednotka: m; Název_objektu: Lišta
 | -1.52 | CEILING | RASTR 3 0.03 m | 1 | 0.03 | 0 | 1 | 1369Dpl0000000199/01 | m3 | Plocha stropu | NEW | 17.27 | 0.03 | 0 | NEMSOK - Object Layer Attributes #1, Kód prvku: PH03.02.3001; Object Layer Attributes #1, Práce: Suché stavební práce; Object Layer Attributes #1, Materiál: RASTR 3; Object Layer Attributes #1, Výška svěšení: 0.35 m; Object Layer Attributes #1, Únosnost bodová: 0.5 kg; Pset_CoveringCommon - Flammability: bez požadavku
 | -1.53 | FLOORING | layer 0.095 m, PŘÍRODNÍ LINOLEUM 0.005 m | 1 | 0.095 | 0 | 1 | 1369Ppl0000000209/01 | m3 | Plocha podlahy | NEW | 36.652 | 0.1 | 0 | NEMSOK - Object Layer Attributes #2, Status: Nový; Object Layer Attributes #2, Kód prvku: PD06.02.0001; Object Layer Attributes #2, Práce: Povlakové podlahy; Object Layer Attributes #2, Číslo_vrstvy: 2; Object Layer Attributes #2, Tloušťka_vrstvy: 0.005 m; Object Layer Attributes #2, Tloušťka: 0 m; Object Layer Attributes #2, Faktor: 1; Object Layer Attributes #2, Označení: I.P1; Object Layer Attributes #2, Materiál: PŘÍRODNÍ LINOLEUM; Object Layer Attributes #2, Vztažná_výška: 0; Object Layer Attributes #2, Delta_výšky: 0; Object Layer Attributes #2, Podlaží: 1.PP; Object Layer Attributes #2, Číslo místnosti: -1.53; Object Layer Attributes #2, Plošná únosnost: 5; Object Layer Attributes #2, Allright_Stavebni_dil_ID: 1369Ppl0000000209/02; Object Layer Attributes #2, Jednotka: m3; Object Layer Attributes #2, Název_objektu: Plocha podlahy
 | -1.53 | SKIRTINGBOARD | FABION |  |  |  |  |  |  |  | NEW | NEMSOK - Kód prvku: PD00.02.0000; Práce: Povlakové podlahy; Faktor: 1; Materiál: FABION; Vztažná_výška: 0; Delta_výšky: 0; Allright_Stavebni_dil_ID: 1369Liš0000001436; Jednotka: m; Název_objektu: Lišta
 | -1.53 | CEILING | RASTR 1 0.03 m | 1 | 0.03 | 0 | 1 | 1369Dpl0000000208/01 | m3 | Plocha stropu | NEW | 36.652 | 0.03 | 0 | NEMSOK - Object Layer Attributes #1, Kód prvku: PH03.02.1001; Object Layer Attributes #1, Práce: Suché stavební práce; Object Layer Attributes #1, Materiál: RASTR 1; Object Layer Attributes #1, Výška svěšení: 0.35 m; Object Layer Attributes #1, Únosnost bodová: 0.5 kg; Pset_CoveringCommon - Flammability: bez požadavku
 | -1.55 | FLOORING | layer 0.095 m, ELEKTROSTATICKÝ VINYL 0.005 m | 1 | 0.095 | 0 | 1 | 1369Ppl0000000218/01 | m3 | Plocha podlahy | NEW | 11.2 | 0.1 | 0 | NEMSOK - Object Layer Attributes #2, Status: Nový; Object Layer Attributes #2, Kód prvku: PD06.02.1001; Object Layer Attributes #2, Práce: Povlakové podlahy; Object Layer Attributes #2, Číslo_vrstvy: 2; Object Layer Attributes #2, Tloušťka_vrstvy: 0.005 m; Object Layer Attributes #2, Tloušťka: 0 m; Object Layer Attributes #2, Faktor: 1; Object Layer Attributes #2, Označení: I.P2; Object Layer Attributes #2, Materiál: ELEKTROSTATICKÝ VINYL; Object Layer Attributes #2, Vztažná_výška: 0; Object Layer Attributes #2, Delta_výšky: 0; Object Layer Attributes #2, Podlaží: 1.PP; Object Layer Attributes #2, Číslo místnosti: -1.55; Object Layer Attributes #2, Plošná únosnost: 5; Object Layer Attributes #2, Allright_Stavebni_dil_ID: 1369Ppl0000000218/02; Object Layer Attributes #2, Jednotka: m3; Object Layer Attributes #2, Název_objektu: Plocha podlahy
 | -1.55 | CEILING | SÁDROVÁ OMÍTKA 0.015 m, MALBA 0.005 m | 1 | 0.015 | 0 | 1 | 1369Dpl0000000217/01 | m3 | Plocha stropu | NEW | 11.2 | 0.02 | 0 | NEMSOK - Object Layer Attributes #1, Kód prvku: OM04.02.1001; Object Layer Attributes #1, Práce: Omítky a štuky; Object Layer Attributes #1, Materiál: SÁDROVÁ OMÍTKA; Object Layer Attributes #1, Způsob provedení: strojní; Object Layer Attributes #2, Status: Nový; Object Layer Attributes #2, Kód prvku: MB03.02.1001; Object Layer Attributes #2, Práce: Malby a nátěry; Object Layer Attributes #2, Číslo_vrstvy: 2; Object Layer Attributes #2, Tloušťka_vrstvy: 0.005 m; Object Layer Attributes #2, Tloušťka: 0 m; Object Layer Attributes #2, Faktor: 1; Object Layer Attributes #2, Materiál: MALBA; Object Layer Attributes #2, Vztažná_výška: 0; Object Layer Attributes #2, Delta_výšky: 0; Object Layer Attributes #2, Podlaží: 1.PP; Object Layer Attributes #2, Allright_Stavebni_dil_ID: 1369Dpl0000000217/02; Object Layer Attributes #2, Jednotka: m3; Object Layer Attributes #2, Název_objektu: Plocha stropu; Object Layer Attributes #2, Způsob provedení: ruční
 | -1.55 | SKIRTINGBOARD | FABION |  |  |  |  |  |  |  | NEW | NEMSOK - Kód prvku: PD00.02.0000; Práce: Povlakové podlahy; Faktor: 1; Materiál: FABION; Vztažná_výška: 0; Delta_výšky: 0; Allright_Stavebni_dil_ID: 1369Liš0000001437; Jednotka: m; Název_objektu: Lišta
 | -1.56 | FLOORING | layer 0.085 m, KERAMICKÁ DLAŽBA 0.015 m | 1 | 0.085 | 0 | 1 | 1369Ppl0000000227/01 | m3 | Plocha podlahy | NEW | 1.93 | 0.1 | 0 | NEMSOK - Object Layer Attributes #2, Status: Nový; Object Layer Attributes #2, Kód prvku: PD01.02.0001; Object Layer Attributes #2, Práce: Obklady a dlažby; Object Layer Attributes #2, Číslo_vrstvy: 2; Object Layer Attributes #2, Tloušťka_vrstvy: 0.015 m; Object Layer Attributes #2, Tloušťka: 0 m; Object Layer Attributes #2, Faktor: 1; Object Layer Attributes #2, Označení: I.P3; Object Layer Attributes #2, Materiál: KERAMICKÁ DLAŽBA; Object Layer Attributes #2, Vztažná_výška: 0; Object Layer Attributes #2, Delta_výšky: 0; Object Layer Attributes #2, Podlaží: 1.PP; Object Layer Attributes #2, Číslo místnosti: -1.56; Object Layer Attributes #2, Plošná únosnost: 5; Object Layer Attributes #2, Allright_Stavebni_dil_ID: 1369Ppl0000000227/02; Object Layer Attributes #2, Jednotka: m3; Object Layer Attributes #2, Název_objektu: Plocha podlahy
 | -1.56 | CEILING | RASTR 2 0.03 m | 1 | 0.03 | 0 | 1 | 1369Dpl0000000226/01 | m3 | Plocha stropu | NEW | 1.93 | 0.03 | 0 | NEMSOK - Object Layer Attributes #1, Kód prvku: PH03.02.2001; Object Layer Attributes #1, Práce: Suché stavební práce; Object Layer Attributes #1, Materiál: RASTR 2; Object Layer Attributes #1, Výška svěšení: 0.35 m; Object Layer Attributes #1, Únosnost bodová: 0.5 kg; Pset_CoveringCommon - Flammability: bez požadavku
 | -1.56a | FLOORING | layer 0.085 m, KERAMICKÁ DLAŽBA 0.015 m | 1 | 0.085 | 0 | 1 | 1369Ppl0000000236/01 | m3 | Plocha podlahy | NEW | 1.537 | 0.1 | 0 | NEMSOK - Object Layer Attributes #2, Status: Nový; Object Layer Attributes #2, Kód prvku: PD01.02.0001; Object Layer Attributes #2, Práce: Obklady a dlažby; Object Layer Attributes #2, Číslo_vrstvy: 2; Object Layer Attributes #2, Tloušťka_vrstvy: 0.015 m; Object Layer Attributes #2, Tloušťka: 0 m; Object Layer Attributes #2, Faktor: 1; Object Layer Attributes #2, Označení: I.P3; Object Layer Attributes #2, Materiál: KERAMICKÁ DLAŽBA; Object Layer Attributes #2, Vztažná_výška: 0; Object Layer Attributes #2, Delta_výšky: 0; Object Layer Attributes #2, Podlaží: 1.PP; Object Layer Attributes #2, Číslo místnosti: -1.56a; Object Layer Attributes #2, Plošná únosnost: 5; Object Layer Attributes #2, Allright_Stavebni_dil_ID: 1369Ppl0000000236/02; Object Layer Attributes #2, Jednotka: m3; Object Layer Attributes #2, Název_objektu: Plocha podlahy
 | -1.56a | CEILING | RASTR 2 0.03 m | 1 | 0.03 | 0 | 1 | 1369Dpl0000000235/01 | m3 | Plocha stropu | NEW | 1.537 | 0.03 | 0 | NEMSOK - Object Layer Attributes #1, Kód prvku: PH03.02.2001; Object Layer Attributes #1, Práce: Suché stavební práce; Object Layer Attributes #1, Materiál: RASTR 2; Object Layer Attributes #1, Výška svěšení: 0.35 m; Object Layer Attributes #1, Únosnost bodová: 0.5 kg; Pset_CoveringCommon - Flammability: bez požadavku
 | -1.40 | FLOORING | layer 0.085 m, KERAMICKÁ DLAŽBA 0.015 m | 1 | 0.085 | 0 | 1 | 1369Ppl0000000370/01 | m3 | Plocha podlahy | NEW | 4.923 | 0.1 | 0 | NEMSOK - Object Layer Attributes #2, Status: Nový; Object Layer Attributes #2, Kód prvku: PD01.02.0001; Object Layer Attributes #2, Práce: Obklady a dlažby; Object Layer Attributes #2, Číslo_vrstvy: 2; Object Layer Attributes #2, Tloušťka_vrstvy: 0.015 m; Object Layer Attributes #2, Tloušťka: 0 m; Object Layer Attributes #2, Faktor: 1; Object Layer Attributes #2, Označení: I.P3; Object Layer Attributes #2, Materiál: KERAMICKÁ DLAŽBA; Object Layer Attributes #2, Vztažná_výška: 0; Object Layer Attributes #2, Delta_výšky: 0; Object Layer Attributes #2, Podlaží: 1.PP; Object Layer Attributes #2, Číslo místnosti: -1.40; Object Layer Attributes #2, Plošná únosnost: 5; Object Layer Attributes #2, Allright_Stavebni_dil_ID: 1369Ppl0000000370/02; Object Layer Attributes #2, Jednotka: m3; Object Layer Attributes #2, Název_objektu: Plocha podlahy
 | -1.40 | CEILING | RASTR 2 0.03 m | 1 | 0.03 | 0 | 1 | 1369Dpl0000000369/01 | m3 | Plocha stropu | NEW | 4.923 | 0.03 | 0 | NEMSOK - Object Layer Attributes #1, Kód prvku: PH03.02.2001; Object Layer Attributes #1, Práce: Suché stavební práce; Object Layer Attributes #1, Materiál: RASTR 2; Object Layer Attributes #1, Výška svěšení: 0.35 m; Object Layer Attributes #1, Únosnost bodová: 0.5 kg; Pset_CoveringCommon - Flammability: bez požadavku
 | -1.41 | FLOORING | layer 0.085 m, KERAMICKÁ DLAŽBA 0.015 m | 1 | 0.085 | 0 | 1 | 1369Ppl0000000381/01 | m3 | Plocha podlahy | NEW | 1.148 | 0.1 | 0 | NEMSOK - Object Layer Attributes #2, Status: Nový; Object Layer Attributes #2, Kód prvku: PD01.02.0001; Object Layer Attributes #2, Práce: Obklady a dlažby; Object Layer Attributes #2, Číslo_vrstvy: 2; Object Layer Attributes #2, Tloušťka_vrstvy: 0.015 m; Object Layer Attributes #2, Tloušťka: 0 m; Object Layer Attributes #2, Faktor: 1; Object Layer Attributes #2, Označení: I.P3; Object Layer Attributes #2, Materiál: KERAMICKÁ DLAŽBA; Object Layer Attributes #2, Vztažná_výška: 0; Object Layer Attributes #2, Delta_výšky: 0; Object Layer Attributes #2, Podlaží: 1.PP; Object Layer Attributes #2, Číslo místnosti: -1.41; Object Layer Attributes #2, Plošná únosnost: 5; Object Layer Attributes #2, Allright_Stavebni_dil_ID: 1369Ppl0000000381/02; Object Layer Attributes #2, Jednotka: m3; Object Layer Attributes #2, Název_objektu: Plocha podlahy
 | -1.41 | CEILING | RASTR 2 0.03 m | 1 | 0.03 | 0 | 1 | 1369Dpl0000000380/01 | m3 | Plocha stropu | NEW | 1.148 | 0.03 | 0 | NEMSOK - Object Layer Attributes #1, Kód prvku: PH03.02.2001; Object Layer Attributes #1, Práce: Suché stavební práce; Object Layer Attributes #1, Materiál: RASTR 2; Object Layer Attributes #1, Výška svěšení: 0.55 m; Object Layer Attributes #1, Únosnost bodová: 0.5 kg; Pset_CoveringCommon - Flammability: bez požadavku
 | -1.42 | FLOORING | layer 0.085 m, KERAMICKÁ DLAŽBA 0.015 m | 1 | 0.085 | 0 | 1 | 1369Ppl0000000390/01 | m3 | Plocha podlahy | NEW | 4.07 | 0.1 | 0 | NEMSOK - Object Layer Attributes #2, Status: Nový; Object Layer Attributes #2, Kód prvku: PD01.02.0001; Object Layer Attributes #2, Práce: Obklady a dlažby; Object Layer Attributes #2, Číslo_vrstvy: 2; Object Layer Attributes #2, Tloušťka_vrstvy: 0.015 m; Object Layer Attributes #2, Tloušťka: 0 m; Object Layer Attributes #2, Faktor: 1; Object Layer Attributes #2, Označení: I.P3; Object Layer Attributes #2, Materiál: KERAMICKÁ DLAŽBA; Object Layer Attributes #2, Vztažná_výška: 0; Object Layer Attributes #2, Delta_výšky: 0; Object Layer Attributes #2, Podlaží: 1.PP; Object Layer Attributes #2, Číslo místnosti: -1.42; Object Layer Attributes #2, Plošná únosnost: 5; Object Layer Attributes #2, Allright_Stavebni_dil_ID: 1369Ppl0000000390/02; Object Layer Attributes #2, Jednotka: m3; Object Layer Attributes #2, Název_objektu: Plocha podlahy
 | -1.42 | CEILING | RASTR 2 0.03 m | 1 | 0.03 | 0 | 1 | 1369Dpl0000000389/01 | m3 | Plocha stropu | NEW | 4.07 | 0.03 | 0 | NEMSOK - Object Layer Attributes #1, Kód prvku: PH03.02.2001; Object Layer Attributes #1, Práce: Suché stavební práce; Object Layer Attributes #1, Materiál: RASTR 2; Object Layer Attributes #1, Výška svěšení: 0.35 m; Object Layer Attributes #1, Únosnost bodová: 0.5 kg; Pset_CoveringCommon - Flammability: bez požadavku
 | -1.43 | FLOORING | layer 0.085 m, KERAMICKÁ DLAŽBA 0.015 m | 1 | 0.085 | 0 | 1 | 1369Ppl0000000399/01 | m3 | Plocha podlahy | NEW | 2.43 | 0.1 | 0 | NEMSOK - Object Layer Attributes #2, Status: Nový; Object Layer Attributes #2, Kód prvku: PD01.02.0001; Object Layer Attributes #2, Práce: Obklady a dlažby; Object Layer Attributes #2, Číslo_vrstvy: 2; Object Layer Attributes #2, Tloušťka_vrstvy: 0.015 m; Object Layer Attributes #2, Tloušťka: 0 m; Object Layer Attributes #2, Faktor: 1; Object Layer Attributes #2, Označení: I.P3; Object Layer Attributes #2, Materiál: KERAMICKÁ DLAŽBA; Object Layer Attributes #2, Vztažná_výška: 0; Object Layer Attributes #2, Delta_výšky: 0; Object Layer Attributes #2, Podlaží: 1.PP; Object Layer Attributes #2, Číslo místnosti: -1.43; Object Layer Attributes #2, Plošná únosnost: 5; Object Layer Attributes #2, Allright_Stavebni_dil_ID: 1369Ppl0000000399/02; Object Layer Attributes #2, Jednotka: m3; Object Layer Attributes #2, Název_objektu: Plocha podlahy
 | -1.43 | CEILING | RASTR 2 0.03 m | 1 | 0.03 | 0 | 1 | 1369Dpl0000000398/01 | m3 | Plocha stropu | NEW | 2.43 | 0.03 | 0 | NEMSOK - Object Layer Attributes #1, Kód prvku: PH03.02.2001; Object Layer Attributes #1, Práce: Suché stavební práce; Object Layer Attributes #1, Materiál: RASTR 2; Object Layer Attributes #1, Výška svěšení: 0.35 m; Object Layer Attributes #1, Únosnost bodová: 0.5 kg; Pset_CoveringCommon - Flammability: bez požadavku
 | -1.44 | FLOORING | layer 0.085 m, KERAMICKÁ DLAŽBA 0.015 m | 1 | 0.085 | 0 | 1 | 1369Ppl0000000408/01 | m3 | Plocha podlahy | NEW | 1.485 | 0.1 | 0 | NEMSOK - Object Layer Attributes #2, Status: Nový; Object Layer Attributes #2, Kód prvku: PD01.02.0001; Object Layer Attributes #2, Práce: Obklady a dlažby; Object Layer Attributes #2, Číslo_vrstvy: 2; Object Layer Attributes #2, Tloušťka_vrstvy: 0.015 m; Object Layer Attributes #2, Tloušťka: 0 m; Object Layer Attributes #2, Faktor: 1; Object Layer Attributes #2, Označení: I.P3; Object Layer Attributes #2, Materiál: KERAMICKÁ DLAŽBA; Object Layer Attributes #2, Vztažná_výška: 0; Object Layer Attributes #2, Delta_výšky: 0; Object Layer Attributes #2, Podlaží: 1.PP; Object Layer Attributes #2, Číslo místnosti: -1.44; Object Layer Attributes #2, Plošná únosnost: 5; Object Layer Attributes #2, Allright_Stavebni_dil_ID: 1369Ppl0000000408/02; Object Layer Attributes #2, Jednotka: m3; Object Layer Attributes #2, Název_objektu: Plocha podlahy
 | -1.44 | CEILING | RASTR 2 0.03 m | 1 | 0.03 | 0 | 1 | 1369Dpl0000000407/01 | m3 | Plocha stropu | NEW | 1.485 | 0.03 | 0 | NEMSOK - Object Layer Attributes #1, Kód prvku: PH03.02.2001; Object Layer Attributes #1, Práce: Suché stavební práce; Object Layer Attributes #1, Materiál: RASTR 2; Object Layer Attributes #1, Výška svěšení: 0.55 m; Object Layer Attributes #1, Únosnost bodová: 0.5 kg; Pset_CoveringCommon - Flammability: bez požadavku
 | -1.45 | FLOORING | layer 0.085 m, KERAMICKÁ DLAŽBA 0.015 m | 1 | 0.085 | 0 | 1 | 1369Ppl0000000419/01 | m3 | Plocha podlahy | NEW | 2.025 | 0.1 | 0 | NEMSOK - Object Layer Attributes #2, Status: Nový; Object Layer Attributes #2, Kód prvku: PD01.02.0001; Object Layer Attributes #2, Práce: Obklady a dlažby; Object Layer Attributes #2, Číslo_vrstvy: 2; Object Layer Attributes #2, Tloušťka_vrstvy: 0.015 m; Object Layer Attributes #2, Tloušťka: 0 m; Object Layer Attributes #2, Faktor: 1; Object Layer Attributes #2, Označení: I.P3; Object Layer Attributes #2, Materiál: KERAMICKÁ DLAŽBA; Object Layer Attributes #2, Vztažná_výška: 0; Object Layer Attributes #2, Delta_výšky: 0; Object Layer Attributes #2, Podlaží: 1.PP; Object Layer Attributes #2, Číslo místnosti: -1.45; Object Layer Attributes #2, Plošná únosnost: 5; Object Layer Attributes #2, Allright_Stavebni_dil_ID: 1369Ppl0000000419/02; Object Layer Attributes #2, Jednotka: m3; Object Layer Attributes #2, Název_objektu: Plocha podlahy
 | -1.45 | CEILING | RASTR 2 0.03 m | 1 | 0.03 | 0 | 1 | 1369Dpl0000000418/01 | m3 | Plocha stropu | NEW | 2.025 | 0.03 | 0 | NEMSOK - Object Layer Attributes #1, Kód prvku: PH03.02.2001; Object Layer Attributes #1, Práce: Suché stavební práce; Object Layer Attributes #1, Materiál: RASTR 2; Object Layer Attributes #1, Výška svěšení: 0.35 m; Object Layer Attributes #1, Únosnost bodová: 0.5 kg; Pset_CoveringCommon - Flammability: bez požadavku
 | -1.54 | FLOORING | layer 0.095 m, PŘÍRODNÍ LINOLEUM 0.005 m | 1 | 0.095 | 0 | 1 | 1369Ppl0000000517/01 | m3 | Plocha podlahy | NEW | 1.305 | 0.1 | 0 | NEMSOK - Object Layer Attributes #2, Status: Nový; Object Layer Attributes #2, Kód prvku: PD06.02.0001; Object Layer Attributes #2, Práce: Povlakové podlahy; Object Layer Attributes #2, Číslo_vrstvy: 2; Object Layer Attributes #2, Tloušťka_vrstvy: 0.005 m; Object Layer Attributes #2, Tloušťka: 0 m; Object Layer Attributes #2, Faktor: 1; Object Layer Attributes #2, Označení: I.P1; Object Layer Attributes #2, Materiál: PŘÍRODNÍ LINOLEUM; Object Layer Attributes #2, Vztažná_výška: 0; Object Layer Attributes #2, Delta_výšky: 0; Object Layer Attributes #2, Podlaží: 1.PP; Object Layer Attributes #2, Číslo místnosti: -1.54; Object Layer Attributes #2, Plošná únosnost: 5; Object Layer Attributes #2, Allright_Stavebni_dil_ID: 1369Ppl0000000517/02; Object Layer Attributes #2, Jednotka: m3; Object Layer Attributes #2, Název_objektu: Plocha podlahy
 | -1.54 | CEILING | SÁDROVÁ OMÍTKA 0.015 m, MALBA 0.005 m | 1 | 0.015 | 0 | 1 | 1369Dpl0000000516/01 | m3 | Plocha stropu | NEW | 1.305 | 0.02 | 0 | NEMSOK - Object Layer Attributes #1, Kód prvku: OM04.02.1001; Object Layer Attributes #1, Práce: Omítky a štuky; Object Layer Attributes #1, Materiál: SÁDROVÁ OMÍTKA; Object Layer Attributes #1, Způsob provedení: strojní; Object Layer Attributes #2, Status: Nový; Object Layer Attributes #2, Kód prvku: MB03.02.1001; Object Layer Attributes #2, Práce: Malby a nátěry; Object Layer Attributes #2, Číslo_vrstvy: 2; Object Layer Attributes #2, Tloušťka_vrstvy: 0.005 m; Object Layer Attributes #2, Tloušťka: 0 m; Object Layer Attributes #2, Faktor: 1; Object Layer Attributes #2, Materiál: MALBA; Object Layer Attributes #2, Vztažná_výška: 0; Object Layer Attributes #2, Delta_výšky: 0; Object Layer Attributes #2, Podlaží: 1.PP; Object Layer Attributes #2, Allright_Stavebni_dil_ID: 1369Dpl0000000516/02; Object Layer Attributes #2, Jednotka: m3; Object Layer Attributes #2, Název_objektu: Plocha stropu; Object Layer Attributes #2, Způsob provedení: ruční
 | -1.54 | SKIRTINGBOARD | FABION |  |  |  |  |  |  |  | NEW | NEMSOK - Kód prvku: PD00.02.0000; Práce: Povlakové podlahy; Faktor: 1; Materiál: FABION; Vztažná_výška: 0; Delta_výšky: 0; Allright_Stavebni_dil_ID: 1369Liš0000001438; Jednotka: m; Název_objektu: Lišta
 | -1.05 | FLOORING | layer 0.08 m, STÁVAJÍCÍ CEMENTOVÝ POTĚR 0.02 m | 1 | 0.08 | 0 | 1 | 1369Ppl0000001176/01 | m3 | Plocha podlahy | EXISTING | 22.984 | 0.1 | 0 | NEMSOK - Object Layer Attributes #2, Status: Stávající; Object Layer Attributes #2, Kód prvku: PD07.02.0002; Object Layer Attributes #2, Práce: Betonářské práce; Object Layer Attributes #2, Číslo_vrstvy: 2; Object Layer Attributes #2, Tloušťka_vrstvy: 0.02 m; Object Layer Attributes #2, Tloušťka: 0 m; Object Layer Attributes #2, Faktor: 1; Object Layer Attributes #2, Materiál: STÁVAJÍCÍ CEMENTOVÝ POTĚR; Object Layer Attributes #2, Vztažná_výška: 0; Object Layer Attributes #2, Delta_výšky: 0; Object Layer Attributes #2, Allright_Stavebni_dil_ID: 1369Ppl0000001176/02; Object Layer Attributes #2, Jednotka: m3; Object Layer Attributes #2, Název_objektu: Plocha podlahy
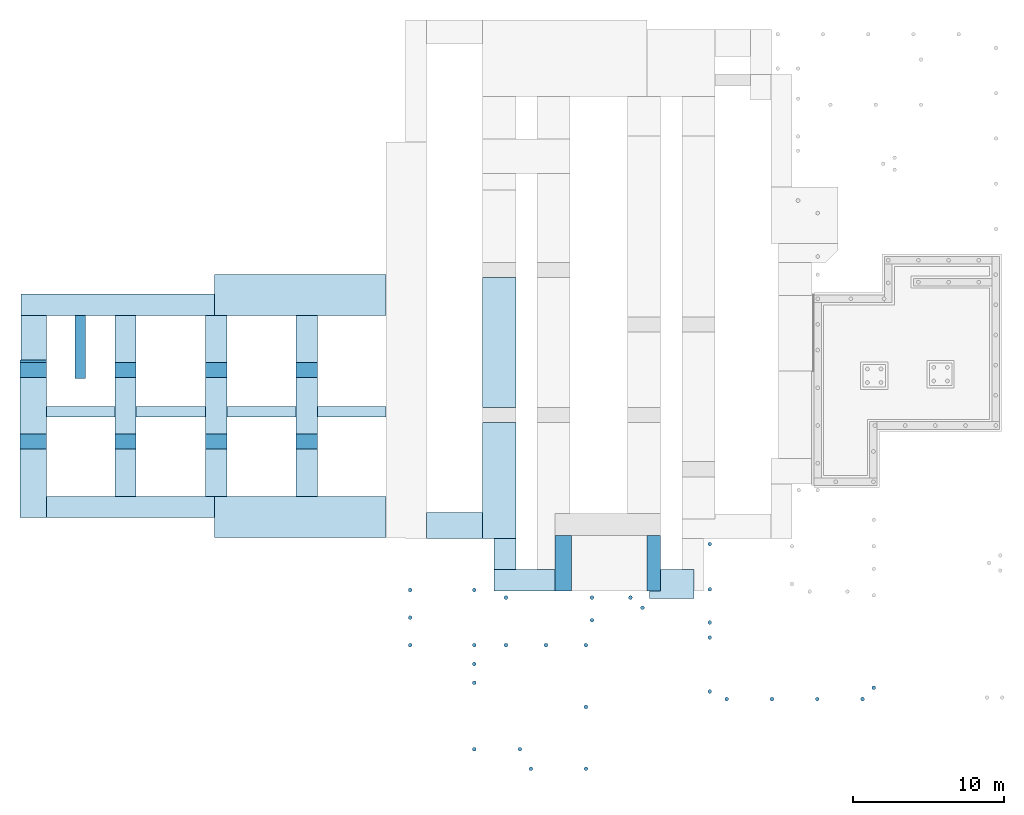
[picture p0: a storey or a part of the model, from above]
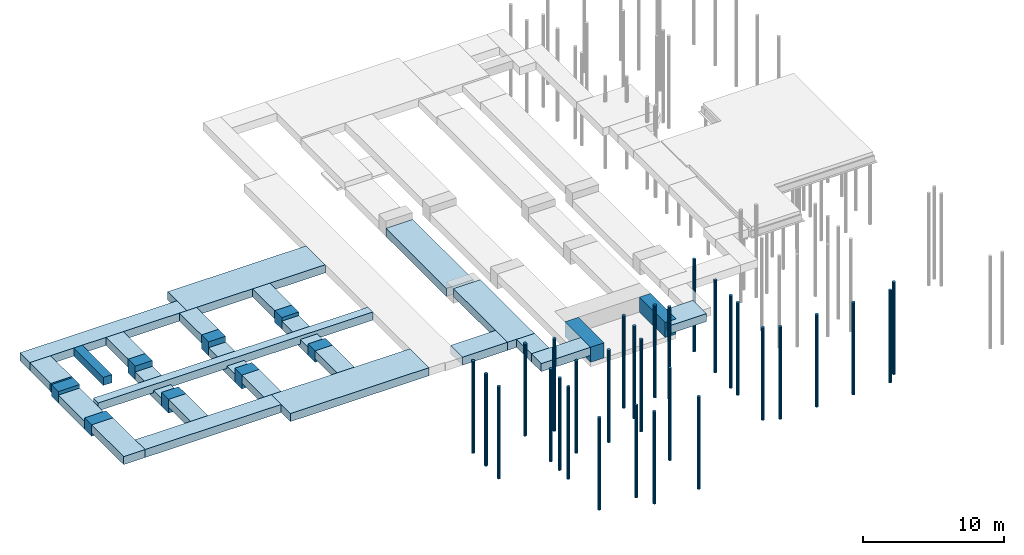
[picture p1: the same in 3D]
Properties of the parts of a building model (IFC4), part 6 of 45

# IfcCovering (314)
Name | In | PredefinedType | Material | Object Layer Attributes #1, Číslo_vrstvy | Object Layer Attributes #1, Tloušťka_vrstvy (m) | Object Layer Attributes #1, Tloušťka (m) = Object Layer Attributes #1, Vztažná_výška = Object Layer Attributes #1, Delta_výšky | Object Layer Attributes #1, Faktor | Object Layer Attributes #1, Allright_Stavebni_dil_ID | Object Layer Attributes #1, Jednotka | Object Layer Attributes #1, Název_objektu | Status | NetArea (m2) | Width (m) | Perimeter (m)
 | -1.05 | CEILING | AKUSTICKÝ OBKLAD 0.05 m | 1 | 0.05 | 0 | 1 | 1369Dpl0000001175/01 | m3 | Plocha stropu | NEW | 22.984 | 0.05 | 0 | NEMSOK - Object Layer Attributes #1, Kód prvku: AI02.02.1001; Object Layer Attributes #1, Práce: Suché stavební práce; Object Layer Attributes #1, Materiál: AKUSTICKÝ OBKLAD; Object Layer Attributes #1, Systém kotvení: Mechanicky kotvený; Pset_CoveringCommon - Flammability: A2-s1
 | -1.57 | FLOORING | layer 0.085 m, KERAMICKÁ DLAŽBA 0.015 m | 1 | 0.085 | 0 | 1 | 1369Ppl0000001548/01 | m3 | Plocha podlahy | NEW | 3.026 | 0.1 | 0 | NEMSOK - Object Layer Attributes #2, Status: Nový; Object Layer Attributes #2, Kód prvku: PD01.02.0001; Object Layer Attributes #2, Práce: Obklady a dlažby; Object Layer Attributes #2, Číslo_vrstvy: 2; Object Layer Attributes #2, Tloušťka_vrstvy: 0.015 m; Object Layer Attributes #2, Tloušťka: 0 m; Object Layer Attributes #2, Faktor: 1; Object Layer Attributes #2, Označení: I.P3; Object Layer Attributes #2, Materiál: KERAMICKÁ DLAŽBA; Object Layer Attributes #2, Vztažná_výška: 0; Object Layer Attributes #2, Delta_výšky: 0; Object Layer Attributes #2, Podlaží: 1.PP; Object Layer Attributes #2, Číslo místnosti: -1.57; Object Layer Attributes #2, Plošná únosnost: 5; Object Layer Attributes #2, Allright_Stavebni_dil_ID: 1369Ppl0000001548/02; Object Layer Attributes #2, Jednotka: m3; Object Layer Attributes #2, Název_objektu: Plocha podlahy
 | -1.57 | CEILING | RASTR 2 0.03 m | 1 | 0.03 | 0 | 1 | 1369Dpl0000001550/01 | m3 | Plocha stropu | NEW | 3.026 | 0.03 | 0 | NEMSOK - Object Layer Attributes #1, Kód prvku: PH03.02.2001; Object Layer Attributes #1, Práce: Suché stavební práce; Object Layer Attributes #1, Materiál: RASTR 2; Object Layer Attributes #1, Výška svěšení: 0.35 m; Object Layer Attributes #1, Únosnost bodová: 0.5 kg; Pset_CoveringCommon - Flammability: bez požadavku
 | -1.41 | FLOORING | layer 0.085 m, KERAMICKÁ DLAŽBA 0.015 m | 1 | 0.085 | 0 | 1 | 1369Ppl0000001764/01 | m3 | Plocha podlahy | NEW | 3.47 | 0.1 | 0 | NEMSOK - Object Layer Attributes #2, Status: Nový; Object Layer Attributes #2, Kód prvku: PD01.02.0001; Object Layer Attributes #2, Práce: Obklady a dlažby; Object Layer Attributes #2, Číslo_vrstvy: 2; Object Layer Attributes #2, Tloušťka_vrstvy: 0.015 m; Object Layer Attributes #2, Tloušťka: 0 m; Object Layer Attributes #2, Faktor: 1; Object Layer Attributes #2, Označení: I.P3; Object Layer Attributes #2, Materiál: KERAMICKÁ DLAŽBA; Object Layer Attributes #2, Vztažná_výška: 0; Object Layer Attributes #2, Delta_výšky: 0; Object Layer Attributes #2, Podlaží: 1.PP; Object Layer Attributes #2, Číslo místnosti: -1.41; Object Layer Attributes #2, Plošná únosnost: 5; Object Layer Attributes #2, Allright_Stavebni_dil_ID: 1369Ppl0000001764/02; Object Layer Attributes #2, Jednotka: m3; Object Layer Attributes #2, Název_objektu: Plocha podlahy
 | -1.41 | CEILING | RASTR 2 0.03 m | 1 | 0.03 | 0 | 1 | 1369Dpl0000001766/01 | m3 | Plocha stropu | NEW | 3.47 | 0.03 | 0 | NEMSOK - Object Layer Attributes #1, Kód prvku: PH03.02.2001; Object Layer Attributes #1, Práce: Suché stavební práce; Object Layer Attributes #1, Materiál: RASTR 2; Object Layer Attributes #1, Výška svěšení: 0.35 m; Object Layer Attributes #1, Únosnost bodová: 0.5 kg; Pset_CoveringCommon - Flammability: bez požadavku
 | -1.38 | FLOORING | layer 0.095 m, PŘÍRODNÍ LINOLEUM 0.005 m | 1 | 0.095 | 0 | 1 | 1369Ppl0000000046/01 | m3 | Plocha podlahy | NEW | 28.459 | 0.1 | 0 | NEMSOK - Object Layer Attributes #2, Status: Nový; Object Layer Attributes #2, Kód prvku: PD06.02.0001; Object Layer Attributes #2, Práce: Povlakové podlahy; Object Layer Attributes #2, Číslo_vrstvy: 2; Object Layer Attributes #2, Tloušťka_vrstvy: 0.005 m; Object Layer Attributes #2, Tloušťka: 0 m; Object Layer Attributes #2, Faktor: 1; Object Layer Attributes #2, Označení: I.P1; Object Layer Attributes #2, Materiál: PŘÍRODNÍ LINOLEUM; Object Layer Attributes #2, Vztažná_výška: 0; Object Layer Attributes #2, Delta_výšky: 0; Object Layer Attributes #2, Podlaží: 1.PP; Object Layer Attributes #2, Číslo místnosti: -1.38; Object Layer Attributes #2, Plošná únosnost: 5; Object Layer Attributes #2, Allright_Stavebni_dil_ID: 1369Ppl0000000046/02; Object Layer Attributes #2, Jednotka: m3; Object Layer Attributes #2, Název_objektu: Plocha podlahy
 | -1.38 | SKIRTINGBOARD | FABION |  |  |  |  |  |  |  | NEW | NEMSOK - Kód prvku: PD00.02.0000; Práce: Povlakové podlahy; Faktor: 1; Materiál: FABION; Vztažná_výška: 0; Delta_výšky: 0; Allright_Stavebni_dil_ID: 1369Liš0000001428; Jednotka: m; Název_objektu: Lišta
 | -1.38 | CEILING | RASTR 1 0.03 m | 1 | 0.03 | 0 | 1 | 1369Dpl0000000045/01 | m3 | Plocha stropu | NEW | 28.459 | 0.03 | 0 | NEMSOK - Object Layer Attributes #1, Kód prvku: PH03.02.1001; Object Layer Attributes #1, Práce: Suché stavební práce; Object Layer Attributes #1, Materiál: RASTR 1; Object Layer Attributes #1, Výška svěšení: 0.35 m; Object Layer Attributes #1, Únosnost bodová: 0.5 kg; Pset_CoveringCommon - Flammability: bez požadavku
 | -1.36 | FLOORING | layer 0.095 m, ELEKTROSTATICKÝ VINYL 0.005 m | 1 | 0.095 | 0 | 1 | 1369Ppl0000000026/01 | m3 | Plocha podlahy | NEW | 16.165 | 0.1 | 0 | NEMSOK - Object Layer Attributes #2, Status: Nový; Object Layer Attributes #2, Kód prvku: PD06.02.1001; Object Layer Attributes #2, Práce: Povlakové podlahy; Object Layer Attributes #2, Číslo_vrstvy: 2; Object Layer Attributes #2, Tloušťka_vrstvy: 0.005 m; Object Layer Attributes #2, Tloušťka: 0 m; Object Layer Attributes #2, Faktor: 1; Object Layer Attributes #2, Označení: I.P2; Object Layer Attributes #2, Materiál: ELEKTROSTATICKÝ VINYL; Object Layer Attributes #2, Vztažná_výška: 0; Object Layer Attributes #2, Delta_výšky: 0; Object Layer Attributes #2, Podlaží: 1.PP; Object Layer Attributes #2, Číslo místnosti: -1.36; Object Layer Attributes #2, Plošná únosnost: 5; Object Layer Attributes #2, Allright_Stavebni_dil_ID: 1369Ppl0000000026/02; Object Layer Attributes #2, Jednotka: m3; Object Layer Attributes #2, Název_objektu: Plocha podlahy
 | -1.36 | SKIRTINGBOARD | FABION |  |  |  |  |  |  |  | NEW | NEMSOK - Kód prvku: PD00.02.0000; Práce: Povlakové podlahy; Faktor: 1; Materiál: FABION; Vztažná_výška: 0; Delta_výšky: 0; Allright_Stavebni_dil_ID: 1369Liš0000001426; Jednotka: m; Název_objektu: Lišta
 | -1.36 | CEILING | RASTR 3 0.03 m | 1 | 0.03 | 0 | 1 | 1369Dpl0000000025/01 | m3 | Plocha stropu | NEW | 16.165 | 0.03 | 0 | NEMSOK - Object Layer Attributes #1, Kód prvku: PH03.02.3001; Object Layer Attributes #1, Práce: Suché stavební práce; Object Layer Attributes #1, Materiál: RASTR 3; Object Layer Attributes #1, Výška svěšení: 0.35 m; Object Layer Attributes #1, Únosnost bodová: 0.5 kg; Pset_CoveringCommon - Flammability: bez požadavku
 | -1.37 | FLOORING | layer 0.095 m, ELEKTROSTATICKÝ VINYL 0.005 m | 1 | 0.095 | 0 | 1 | 1369Ppl0000000037/01 | m3 | Plocha podlahy | NEW | 24.09 | 0.1 | 0 | NEMSOK - Object Layer Attributes #2, Status: Nový; Object Layer Attributes #2, Kód prvku: PD06.02.1001; Object Layer Attributes #2, Práce: Povlakové podlahy; Object Layer Attributes #2, Číslo_vrstvy: 2; Object Layer Attributes #2, Tloušťka_vrstvy: 0.005 m; Object Layer Attributes #2, Tloušťka: 0 m; Object Layer Attributes #2, Faktor: 1; Object Layer Attributes #2, Označení: I.P2; Object Layer Attributes #2, Materiál: ELEKTROSTATICKÝ VINYL; Object Layer Attributes #2, Vztažná_výška: 0; Object Layer Attributes #2, Delta_výšky: 0; Object Layer Attributes #2, Podlaží: 1.PP; Object Layer Attributes #2, Číslo místnosti: -1.37; Object Layer Attributes #2, Plošná únosnost: 5; Object Layer Attributes #2, Allright_Stavebni_dil_ID: 1369Ppl0000000037/02; Object Layer Attributes #2, Jednotka: m3; Object Layer Attributes #2, Název_objektu: Plocha podlahy
 | -1.37 | SKIRTINGBOARD | FABION |  |  |  |  |  |  |  | NEW | NEMSOK - Kód prvku: PD00.02.0000; Práce: Povlakové podlahy; Faktor: 1; Materiál: FABION; Vztažná_výška: 0; Delta_výšky: 0; Allright_Stavebni_dil_ID: 1369Liš0000001427; Jednotka: m; Název_objektu: Lišta
 | -1.37 | CEILING | RASTR 3 0.03 m | 1 | 0.03 | 0 | 1 | 1369Dpl0000000036/01 | m3 | Plocha stropu | NEW | 24.09 | 0.03 | 0 | NEMSOK - Object Layer Attributes #1, Kód prvku: PH03.02.3001; Object Layer Attributes #1, Práce: Suché stavební práce; Object Layer Attributes #1, Materiál: RASTR 3; Object Layer Attributes #1, Výška svěšení: 0.35 m; Object Layer Attributes #1, Únosnost bodová: 0.5 kg; Pset_CoveringCommon - Flammability: bez požadavku
I.P1 | -1.58 | FLOORING | layer 0.095 m, PŘÍRODNÍ LINOLEUM 0.005 m | 1 | 0.095 | 0 | 1 | 1369Ppl0000000542/01 | m3 | Plocha podlahy | NEW | 7.41 | 0.1 | 0 | NEMSOK - Object Layer Attributes #2, Status: Nový; Object Layer Attributes #2, Kód prvku: PD06.02.0001; Object Layer Attributes #2, Práce: Povlakové podlahy; Object Layer Attributes #2, Číslo_vrstvy: 2; Object Layer Attributes #2, Tloušťka_vrstvy: 0.005 m; Object Layer Attributes #2, Tloušťka: 0 m; Object Layer Attributes #2, Faktor: 1; Object Layer Attributes #2, Označení: I.P1, I.P5; Object Layer Attributes #2, Materiál: PŘÍRODNÍ LINOLEUM; Object Layer Attributes #2, Vztažná_výška: 0; Object Layer Attributes #2, Delta_výšky: 0; Object Layer Attributes #2, Podlaží: 1.PP; Object Layer Attributes #2, Číslo místnosti: -1.58; Object Layer Attributes #2, Plošná únosnost: 5; Object Layer Attributes #2, Allright_Stavebni_dil_ID: 1369Ppl0000000542/02; Object Layer Attributes #2, Jednotka: m3; Object Layer Attributes #2, Název_objektu: Plocha podlahy; Object Layer Attributes #1, Označení: I.P1
 | -1.58 | CEILING | SÁDROVÁ OMÍTKA 0.015 m, RASTR 1 0.03 m | 1 | 0.015 | 0 | 1 | 1369Dpl0000000541/01 | m3 | Plocha stropu | NEW | 7.41 | 0.045 | 0 | NEMSOK - Object Layer Attributes #1, Kód prvku: OM04.02.1001; Object Layer Attributes #1, Práce: Omítky a štuky; Object Layer Attributes #1, Materiál: SÁDROVÁ OMÍTKA; Object Layer Attributes #1, Způsob provedení: strojní; Object Layer Attributes #2, Status: Nový; Object Layer Attributes #2, Kód prvku: PH03.02.1001; Object Layer Attributes #2, Práce: Suché stavební práce; Object Layer Attributes #2, Číslo_vrstvy: 2; Object Layer Attributes #2, Tloušťka_vrstvy: 0.03 m; Object Layer Attributes #2, Tloušťka: 0 m; Object Layer Attributes #2, Faktor: 1; Object Layer Attributes #2, Materiál: RASTR 1; Object Layer Attributes #2, Vztažná_výška: 0; Object Layer Attributes #2, Delta_výšky: 0; Object Layer Attributes #2, Allright_Stavebni_dil_ID: 1369Dpl0000000541/02; Object Layer Attributes #2, Jednotka: m3; Object Layer Attributes #2, Název_objektu: Plocha stropu; Object Layer Attributes #2, Požární odolnost: bez požadavku; Object Layer Attributes #2, Výška svěšení: 0.55 m; Object Layer Attributes #2, Únosnost bodová: 0.5 kg
 | -1.58 | SKIRTINGBOARD | FABION |  |  |  |  |  |  |  | NEW | NEMSOK - Kód prvku: PD00.02.0000; Práce: Povlakové podlahy; Faktor: 1; Materiál: FABION; Vztažná_výška: 0; Delta_výšky: 0; Allright_Stavebni_dil_ID: 1369Liš0000001411; Jednotka: m; Název_objektu: Lišta
 | -1.64 | FLOORING | layer 0.097 m, EPOXIDOVÁ STĚRKA 0.003 m | 1 | 0.097 | 0 | 1 | 1369Ppl0000000551/01 | m3 | Plocha podlahy | NEW | 9.076 | 0.1 | 0 | NEMSOK - Object Layer Attributes #2, Status: Nový; Object Layer Attributes #2, Kód prvku: PD04.02.0001; Object Layer Attributes #2, Práce: Potěry a stěrky; Object Layer Attributes #2, Číslo_vrstvy: 2; Object Layer Attributes #2, Tloušťka_vrstvy: 0.003 m; Object Layer Attributes #2, Tloušťka: 0 m; Object Layer Attributes #2, Faktor: 1; Object Layer Attributes #2, Označení: I.P4; Object Layer Attributes #2, Materiál: EPOXIDOVÁ STĚRKA; Object Layer Attributes #2, Vztažná_výška: 0; Object Layer Attributes #2, Delta_výšky: 0; Object Layer Attributes #2, Podlaží: 1.PP; Object Layer Attributes #2, Číslo místnosti: -1.64; Object Layer Attributes #2, Plošná únosnost: 5; Object Layer Attributes #2, Allright_Stavebni_dil_ID: 1369Ppl0000000551/02; Object Layer Attributes #2, Jednotka: m3; Object Layer Attributes #2, Název_objektu: Plocha podlahy
 | -1.64 | CEILING | AKUSTICKÝ OBKLAD 0.05 m | 1 | 0.05 | 0 | 1 | 1369Dpl0000000550/01 | m3 | Plocha stropu | NEW | 9.076 | 0.05 | 0 | NEMSOK - Object Layer Attributes #1, Kód prvku: AI02.02.1001; Object Layer Attributes #1, Práce: Suché stavební práce; Object Layer Attributes #1, Materiál: AKUSTICKÝ OBKLAD; Object Layer Attributes #1, Systém kotvení: Mechanicky kotvený; Pset_CoveringCommon - Flammability: A2-s1
 | -1.64 | SKIRTINGBOARD | EPOXIDOVÁ STĚRKA |  |  |  |  |  |  |  | NEW | NEMSOK - Kód prvku: PD00.02.0000; Práce: Potěry a stěrky; Faktor: 1; Materiál: EPOXIDOVÁ STĚRKA; Vztažná_výška: 0; Delta_výšky: 0; Allright_Stavebni_dil_ID: 1369Liš0000001410; Jednotka: m; Název_objektu: Lišta
 | -1.60 | FLOORING | layer 0.297 m, EPOXIDOVÁ STĚRKA 0.003 m | 1 | 0.297 | 0 | 1 | 1369Ppl0000000560/01 | m3 | Plocha podlahy | NEW | 8.352 | 0.3 | 0 | NEMSOK - Object Layer Attributes #2, Status: Nový; Object Layer Attributes #2, Kód prvku: PD04.02.0001; Object Layer Attributes #2, Práce: Potěry a stěrky; Object Layer Attributes #2, Číslo_vrstvy: 2; Object Layer Attributes #2, Tloušťka_vrstvy: 0.003 m; Object Layer Attributes #2, Tloušťka: 0 m; Object Layer Attributes #2, Faktor: 1; Object Layer Attributes #2, Označení: I.P6; Object Layer Attributes #2, Materiál: EPOXIDOVÁ STĚRKA; Object Layer Attributes #2, Vztažná_výška: 0; Object Layer Attributes #2, Delta_výšky: 0; Object Layer Attributes #2, Podlaží: 1.PP; Object Layer Attributes #2, Číslo místnosti: -1.60; Object Layer Attributes #2, Plošná únosnost: 5; Object Layer Attributes #2, Allright_Stavebni_dil_ID: 1369Ppl0000000560/02; Object Layer Attributes #2, Jednotka: m3; Object Layer Attributes #2, Název_objektu: Plocha podlahy
 | -1.60 | CEILING | MALBA 0.005 m | 1 | 0.005 | 0 | 1 | 1369Dpl0000000559/01 | m3 | Plocha stropu | NEW | 8.352 | 0.005 | 0 | NEMSOK - Object Layer Attributes #1, Kód prvku: MB03.02.1001; Object Layer Attributes #1, Práce: Malby a nátěry; Object Layer Attributes #1, Materiál: MALBA; Object Layer Attributes #1, Podlaží: 1.PP; Object Layer Attributes #1, Způsob provedení: ruční
 | -1.60 | SKIRTINGBOARD | EPOXIDOVÁ STĚRKA |  |  |  |  |  |  |  | NEW | NEMSOK - Kód prvku: PD00.02.0000; Práce: Potěry a stěrky; Faktor: 1; Materiál: EPOXIDOVÁ STĚRKA; Vztažná_výška: 0; Delta_výšky: 0; Allright_Stavebni_dil_ID: 1369Liš0000001412; Jednotka: m; Název_objektu: Lišta
 | -1.61 | FLOORING | layer 0.295 m, PŘÍRODNÍ LINOLEUM 0.005 m | 1 | 0.295 | 0 | 1 | 1369Ppl0000000569/01 | m3 | Plocha podlahy | NEW | 16.75 | 0.3 | 0 | NEMSOK - Object Layer Attributes #2, Status: Nový; Object Layer Attributes #2, Kód prvku: PD06.02.0001; Object Layer Attributes #2, Práce: Povlakové podlahy; Object Layer Attributes #2, Číslo_vrstvy: 2; Object Layer Attributes #2, Tloušťka_vrstvy: 0.005 m; Object Layer Attributes #2, Tloušťka: 0 m; Object Layer Attributes #2, Faktor: 1; Object Layer Attributes #2, Označení: I.P5; Object Layer Attributes #2, Materiál: PŘÍRODNÍ LINOLEUM; Object Layer Attributes #2, Vztažná_výška: 0; Object Layer Attributes #2, Delta_výšky: 0; Object Layer Attributes #2, Podlaží: 1.PP; Object Layer Attributes #2, Číslo místnosti: -1.61; Object Layer Attributes #2, Plošná únosnost: 5; Object Layer Attributes #2, Allright_Stavebni_dil_ID: 1369Ppl0000000569/02; Object Layer Attributes #2, Jednotka: m3; Object Layer Attributes #2, Název_objektu: Plocha podlahy
 | -1.61 | SKIRTINGBOARD | FABION |  |  |  |  |  |  |  | NEW | NEMSOK - Kód prvku: PD00.02.0000; Práce: Povlakové podlahy; Faktor: 1; Materiál: FABION; Vztažná_výška: 0; Delta_výšky: 0; Allright_Stavebni_dil_ID: 1369Liš0000001414; Jednotka: m; Název_objektu: Lišta
 | -1.61 | CEILING | RASTR 1 0.03 m | 1 | 0.03 | 0 | 1 | 1369Dpl0000000568/01 | m3 | Plocha stropu | NEW | 16.75 | 0.03 | 0 | NEMSOK - Object Layer Attributes #1, Kód prvku: PH03.02.1001; Object Layer Attributes #1, Práce: Suché stavební práce; Object Layer Attributes #1, Materiál: RASTR 1; Object Layer Attributes #1, Výška svěšení: 0.2 m; Object Layer Attributes #1, Únosnost bodová: 0.5 kg; Pset_CoveringCommon - Flammability: bez požadavku
 | -1.62 | FLOORING | layer 0.295 m, PŘÍRODNÍ LINOLEUM 0.005 m | 1 | 0.295 | 0 | 1 | 1369Ppl0000000578/01 | m3 | Plocha podlahy | NEW | 28.32 | 0.3 | 0 | NEMSOK - Object Layer Attributes #2, Status: Nový; Object Layer Attributes #2, Kód prvku: PD06.02.0001; Object Layer Attributes #2, Práce: Povlakové podlahy; Object Layer Attributes #2, Číslo_vrstvy: 2; Object Layer Attributes #2, Tloušťka_vrstvy: 0.005 m; Object Layer Attributes #2, Tloušťka: 0 m; Object Layer Attributes #2, Faktor: 1; Object Layer Attributes #2, Označení: I.P5; Object Layer Attributes #2, Materiál: PŘÍRODNÍ LINOLEUM; Object Layer Attributes #2, Vztažná_výška: 0; Object Layer Attributes #2, Delta_výšky: 0; Object Layer Attributes #2, Podlaží: 1.PP; Object Layer Attributes #2, Číslo místnosti: -1.62; Object Layer Attributes #2, Plošná únosnost: 5; Object Layer Attributes #2, Allright_Stavebni_dil_ID: 1369Ppl0000000578/02; Object Layer Attributes #2, Jednotka: m3; Object Layer Attributes #2, Název_objektu: Plocha podlahy
 | -1.62 | SKIRTINGBOARD | FABION |  |  |  |  |  |  |  | NEW | NEMSOK - Kód prvku: PD00.02.0000; Práce: Povlakové podlahy; Faktor: 1; Materiál: FABION; Vztažná_výška: 0; Delta_výšky: 0; Allright_Stavebni_dil_ID: 1369Liš0000001415; Jednotka: m; Název_objektu: Lišta
 | -1.62 | CEILING | RASTR 1 0.03 m | 1 | 0.03 | 0 | 1 | 1369Dpl0000000577/01 | m3 | Plocha stropu | NEW | 28.32 | 0.03 | 0 | NEMSOK - Object Layer Attributes #1, Kód prvku: PH03.02.1001; Object Layer Attributes #1, Práce: Suché stavební práce; Object Layer Attributes #1, Materiál: RASTR 1; Object Layer Attributes #1, Výška svěšení: 0.2 m; Object Layer Attributes #1, Únosnost bodová: 0.5 kg; Pset_CoveringCommon - Flammability: bez požadavku
 | -1.63 | FLOORING | layer 0.297 m, EPOXIDOVÁ STĚRKA 0.003 m | 1 | 0.297 | 0 | 1 | 1369Ppl0000000587/01 | m3 | Plocha podlahy | NEW | 51.486 | 0.3 | 0 | NEMSOK - Object Layer Attributes #2, Status: Nový; Object Layer Attributes #2, Kód prvku: PD04.02.0001; Object Layer Attributes #2, Práce: Potěry a stěrky; Object Layer Attributes #2, Číslo_vrstvy: 2; Object Layer Attributes #2, Tloušťka_vrstvy: 0.003 m; Object Layer Attributes #2, Tloušťka: 0 m; Object Layer Attributes #2, Faktor: 1; Object Layer Attributes #2, Označení: I.P6; Object Layer Attributes #2, Materiál: EPOXIDOVÁ STĚRKA; Object Layer Attributes #2, Vztažná_výška: 0; Object Layer Attributes #2, Delta_výšky: 0; Object Layer Attributes #2, Podlaží: 1.PP; Object Layer Attributes #2, Číslo místnosti: -1.63; Object Layer Attributes #2, Plošná únosnost: 5; Object Layer Attributes #2, Allright_Stavebni_dil_ID: 1369Ppl0000000587/02; Object Layer Attributes #2, Jednotka: m3; Object Layer Attributes #2, Název_objektu: Plocha podlahy
 | -1.63 | CEILING | AKUSTICKÝ OBKLAD 0.05 m | 1 | 0.05 | 0 | 1 | 1369Dpl0000000586/01 | m3 | Plocha stropu | NEW | 51.486 | 0.05 | 0 | NEMSOK - Object Layer Attributes #1, Kód prvku: AI02.02.1001; Object Layer Attributes #1, Práce: Suché stavební práce; Object Layer Attributes #1, Materiál: AKUSTICKÝ OBKLAD; Object Layer Attributes #1, Systém kotvení: Mechanicky kotvený; Pset_CoveringCommon - Flammability: A2-s1
 | -1.63 | SKIRTINGBOARD | EPOXIDOVÁ STĚRKA |  |  |  |  |  |  |  | NEW | NEMSOK - Kód prvku: PD00.02.0000; Práce: Potěry a stěrky; Faktor: 1; Materiál: EPOXIDOVÁ STĚRKA; Vztažná_výška: 0; Delta_výšky: 0; Allright_Stavebni_dil_ID: 1369Liš0000001416; Jednotka: m; Název_objektu: Lišta
 | -1.59 | FLOORING | layer 0.095 m, ELEKTROSTATICKÝ VINYL 0.005 m | 1 | 0.095 | 0 | 1 | 1369Ppl0000000602/01 | m3 | Plocha podlahy | NEW | 22.61 | 0.1 | 0 | NEMSOK - Object Layer Attributes #2, Status: Nový; Object Layer Attributes #2, Kód prvku: PD06.02.1001; Object Layer Attributes #2, Práce: Povlakové podlahy; Object Layer Attributes #2, Číslo_vrstvy: 2; Object Layer Attributes #2, Tloušťka_vrstvy: 0.005 m; Object Layer Attributes #2, Tloušťka: 0 m; Object Layer Attributes #2, Faktor: 1; Object Layer Attributes #2, Označení: I.P2; Object Layer Attributes #2, Materiál: ELEKTROSTATICKÝ VINYL; Object Layer Attributes #2, Vztažná_výška: 0; Object Layer Attributes #2, Delta_výšky: 0; Object Layer Attributes #2, Podlaží: 1.PP; Object Layer Attributes #2, Číslo místnosti: -1.59; Object Layer Attributes #2, Plošná únosnost: 5; Object Layer Attributes #2, Allright_Stavebni_dil_ID: 1369Ppl0000000602/02; Object Layer Attributes #2, Jednotka: m3; Object Layer Attributes #2, Název_objektu: Plocha podlahy
 | -1.59 | CEILING | SÁDROVÁ OMÍTKA 0.015 m, MALBA 0.005 m | 1 | 0.015 | 0 | 1 | 1369Dpl0000000601/01 | m3 | Plocha stropu | NEW | 22.61 | 0.02 | 0 | NEMSOK - Object Layer Attributes #1, Kód prvku: OM04.02.1001; Object Layer Attributes #1, Práce: Omítky a štuky; Object Layer Attributes #1, Materiál: SÁDROVÁ OMÍTKA; Object Layer Attributes #1, Způsob provedení: strojní; Object Layer Attributes #2, Status: Nový; Object Layer Attributes #2, Kód prvku: MB03.02.1001; Object Layer Attributes #2, Práce: Malby a nátěry; Object Layer Attributes #2, Číslo_vrstvy: 2; Object Layer Attributes #2, Tloušťka_vrstvy: 0.005 m; Object Layer Attributes #2, Tloušťka: 0 m; Object Layer Attributes #2, Faktor: 1; Object Layer Attributes #2, Materiál: MALBA; Object Layer Attributes #2, Vztažná_výška: 0; Object Layer Attributes #2, Delta_výšky: 0; Object Layer Attributes #2, Podlaží: 1.PP; Object Layer Attributes #2, Allright_Stavebni_dil_ID: 1369Dpl0000000601/02; Object Layer Attributes #2, Jednotka: m3; Object Layer Attributes #2, Název_objektu: Plocha stropu; Object Layer Attributes #2, Způsob provedení: ruční
 | -1.59 | SKIRTINGBOARD | SOKLOVÁ PVC LIŠTA |  |  |  |  |  |  |  | NEW | NEMSOK - Kód prvku: PD00.02.0000; Práce: Povlakové podlahy; Faktor: 1; Materiál: SOKLOVÁ PVC LIŠTA; Vztažná_výška: 0; Delta_výšky: 0; Allright_Stavebni_dil_ID: 1369Liš0000001409; Jednotka: m; Název_objektu: Lišta
 | -1.19 | FLOORING | layer 0.085 m, STÁVAJÍCÍ KERAMICKÁ DLAŽBA 0.015 m | 1 | 0.085 | 0 | 1 | 1369Ppl0000000877/01 | m3 | Plocha podlahy | EXISTING | 85.169 | 0.1 | 0 | NEMSOK - Object Layer Attributes #2, Status: Stávající; Object Layer Attributes #2, Kód prvku: PD01.02.0002; Object Layer Attributes #2, Práce: Obklady a dlažby; Object Layer Attributes #2, Číslo_vrstvy: 2; Object Layer Attributes #2, Tloušťka_vrstvy: 0.015 m; Object Layer Attributes #2, Tloušťka: 0 m; Object Layer Attributes #2, Faktor: 1; Object Layer Attributes #2, Materiál: STÁVAJÍCÍ KERAMICKÁ DLAŽBA; Object Layer Attributes #2, Vztažná_výška: 0; Object Layer Attributes #2, Delta_výšky: 0; Object Layer Attributes #2, Allright_Stavebni_dil_ID: 1369Ppl0000000877/02; Object Layer Attributes #2, Jednotka: m3; Object Layer Attributes #2, Název_objektu: Plocha podlahy
 | -1.19 | CEILING | STÁVAJÍCÍ KAZETOVÝ PODHLED 0.03 m | 1 | 0.03 | 0 | 1 | 1369Dpl0000000882/01 | m3 | Plocha stropu | EXISTING | 85.169 | 0.03 | 0 | NEMSOK - Object Layer Attributes #1, Kód prvku: PH03.02.9001; Object Layer Attributes #1, Práce: Suché stavební práce; Object Layer Attributes #1, Materiál: STÁVAJÍCÍ KAZETOVÝ PODHLED
I.P5 | -1.58 | FLOORING | layer 0.295 m, PŘÍRODNÍ LINOLEUM 0.005 m | 1 | 0.295 | 0 | 1 | 1369Ppl0000001086/01 | m3 | Plocha podlahy | NEW | 13.982 | 0.3 | 0 | NEMSOK - Object Layer Attributes #2, Status: Nový; Object Layer Attributes #2, Kód prvku: PD06.02.0001; Object Layer Attributes #2, Práce: Povlakové podlahy; Object Layer Attributes #2, Číslo_vrstvy: 2; Object Layer Attributes #2, Tloušťka_vrstvy: 0.005 m; Object Layer Attributes #2, Tloušťka: 0 m; Object Layer Attributes #2, Faktor: 1; Object Layer Attributes #2, Označení: I.P1, I.P5; Object Layer Attributes #2, Materiál: PŘÍRODNÍ LINOLEUM; Object Layer Attributes #2, Vztažná_výška: 0; Object Layer Attributes #2, Delta_výšky: 0; Object Layer Attributes #2, Podlaží: 1.PP; Object Layer Attributes #2, Číslo místnosti: -1.58; Object Layer Attributes #2, Plošná únosnost: 5; Object Layer Attributes #2, Allright_Stavebni_dil_ID: 1369Ppl0000001086/02; Object Layer Attributes #2, Jednotka: m3; Object Layer Attributes #2, Název_objektu: Plocha podlahy; Object Layer Attributes #1, Označení: I.P5
 | -1.58 | CEILING | SÁDROVÁ OMÍTKA 0.015 m, RASTR 1 0.03 m | 1 | 0.015 | 0 | 1 | 1369Dpl0000001091/01 | m3 | Plocha stropu | NEW | 13.982 | 0.045 | 0 | NEMSOK - Object Layer Attributes #1, Kód prvku: OM04.02.1001; Object Layer Attributes #1, Práce: Omítky a štuky; Object Layer Attributes #1, Materiál: SÁDROVÁ OMÍTKA; Object Layer Attributes #1, Způsob provedení: strojní; Object Layer Attributes #2, Status: Nový; Object Layer Attributes #2, Kód prvku: PH03.02.1001; Object Layer Attributes #2, Práce: Suché stavební práce; Object Layer Attributes #2, Číslo_vrstvy: 2; Object Layer Attributes #2, Tloušťka_vrstvy: 0.03 m; Object Layer Attributes #2, Tloušťka: 0 m; Object Layer Attributes #2, Faktor: 1; Object Layer Attributes #2, Materiál: RASTR 1; Object Layer Attributes #2, Vztažná_výška: 0; Object Layer Attributes #2, Delta_výšky: 0; Object Layer Attributes #2, Allright_Stavebni_dil_ID: 1369Dpl0000001091/02; Object Layer Attributes #2, Jednotka: m3; Object Layer Attributes #2, Název_objektu: Plocha stropu; Object Layer Attributes #2, Požární odolnost: bez požadavku; Object Layer Attributes #2, Výška svěšení: 0.5 m; Object Layer Attributes #2, Únosnost bodová: 0.5 kg
 | -1.58 | SKIRTINGBOARD | FABION |  |  |  |  |  |  |  | NEW | NEMSOK - Kód prvku: PD00.02.0000; Práce: Povlakové podlahy; Faktor: 1; Materiál: FABION; Vztažná_výška: 0; Delta_výšky: 0; Allright_Stavebni_dil_ID: 1369Liš0000001413; Jednotka: m; Název_objektu: Lišta
 | -1.02 | FLOORING | STÁVAJÍCÍ LINO 0.005 m | 1 | 0.005 | 0 | 1 | 1369Ppl0000001288/01 | m3 | Plocha podlahy | EXISTING | 41.014 | 0.005 | 0 | NEMSOK - Object Layer Attributes #1, Kód prvku: PD06.02.0002; Object Layer Attributes #1, Práce: Povlakové podlahy; Object Layer Attributes #1, Materiál: STÁVAJÍCÍ LINO
 | -1.02 | CEILING | RASTR 1 0.03 m | 1 | 0.03 | 0 | 1 | 1369Dpl0000001287/01 | m3 | Plocha stropu | NEW | 41.014 | 0.03 | 0 | NEMSOK - Object Layer Attributes #1, Kód prvku: PH03.02.1001; Object Layer Attributes #1, Práce: Suché stavební práce; Object Layer Attributes #1, Materiál: RASTR 1; Object Layer Attributes #1, Výška svěšení: 0.35 m; Object Layer Attributes #1, Únosnost bodová: 0.5 kg; Pset_CoveringCommon - Flammability: bez požadavku
 | Půdorys 1.NP | CLADDING | KERAMICKÝ OBKLAD 0.015 m | 1 | 0.015 |  | 1 | 1452Spl1096101371/01 | m2 | Plocha stěny |  | 2.688 | 0.015 | NEMSOK - Object Layer Attributes #1, Práce: Obklady a dlažby; Object Layer Attributes #1, Materiál: KERAMICKÝ OBKLAD; Qto_CoveringBaseQuantities - GrossArea: 2.688 m2
 | Půdorys 1.NP | FLOORING | KERAMICKÝ OBKLAD 0.015 m | 1 | 0.015 |  | 1 | 1452Ppl1096101372/01 | m2 | Plocha podlahy |  | 0.175 | 0.015 | 0 | NEMSOK - Object Layer Attributes #1, Práce: Obklady a dlažby; Object Layer Attributes #1, Materiál: KERAMICKÝ OBKLAD
 | Půdorys 1.NP | CLADDING | KERAMICKÝ OBKLAD 0.015 m | 1 | 0.015 |  | 1 | 1452Spl1096101386/01 | m2 | Plocha stěny |  | 2.75 | 0.015 | NEMSOK - Object Layer Attributes #1, Práce: Obklady a dlažby; Object Layer Attributes #1, Materiál: KERAMICKÝ OBKLAD; Qto_CoveringBaseQuantities - GrossArea: 2.75 m2
 | Půdorys 1.NP | FLOORING | KERAMICKÝ OBKLAD 0.015 m | 1 | 0.015 |  | 1 | 1452Ppl1096101387/01 | m2 | Plocha podlahy |  | 0.18 | 0.015 | 0 | NEMSOK - Object Layer Attributes #1, Práce: Obklady a dlažby; Object Layer Attributes #1, Materiál: KERAMICKÝ OBKLAD
 | Půdorys 1.NP | CLADDING | KERAMICKÝ OBKLAD 0.015 m | 1 | 0.015 |  | 1 | 1452Spl1096115481/01 | m2 | Plocha stěny |  | 0.683 | 0.015 | NEMSOK - Object Layer Attributes #1, Práce: Obklady a dlažby; Object Layer Attributes #1, Materiál: KERAMICKÝ OBKLAD; Qto_CoveringBaseQuantities - GrossArea: 0.683 m2
 | Půdorys 1.NP | FLOORING | KERAMICKÝ OBKLAD 0.015 m | 1 | 0.015 |  | 1 | 1452Ppl1096115482/01 | m2 | Plocha podlahy |  | 0.148 | 0.015 | 0 | NEMSOK - Object Layer Attributes #1, Práce: Obklady a dlažby; Object Layer Attributes #1, Materiál: KERAMICKÝ OBKLAD
 | Půdorys 1.NP | CLADDING | KERAMICKÝ OBKLAD 0.015 m | 1 | 0.015 |  | 1 | 1452Spl1096115456/01 | m2 | Plocha stěny |  | 0.683 | 0.015 | NEMSOK - Object Layer Attributes #1, Práce: Obklady a dlažby; Object Layer Attributes #1, Materiál: KERAMICKÝ OBKLAD; Qto_CoveringBaseQuantities - GrossArea: 0.683 m2
 | Půdorys 1.NP | FLOORING | KERAMICKÝ OBKLAD 0.015 m | 1 | 0.015 |  | 1 | 1452Ppl1096115457/01 | m2 | Plocha podlahy |  | 0.148 | 0.015 | 0 | NEMSOK - Object Layer Attributes #1, Práce: Obklady a dlažby; Object Layer Attributes #1, Materiál: KERAMICKÝ OBKLAD
 | Půdorys 1.NP | CLADDING | KERAMICKÝ OBKLAD 0.015 m | 1 | 0.015 |  | 1 | 1452Spl1096118685/01 | m2 | Plocha stěny |  | 3.96 | 0.015 | NEMSOK - Object Layer Attributes #1, Práce: Obklady a dlažby; Object Layer Attributes #1, Materiál: KERAMICKÝ OBKLAD; Qto_CoveringBaseQuantities - GrossArea: 3.96 m2
 | Půdorys 1.NP | FLOORING | KERAMICKÝ OBKLAD 0.015 m | 1 | 0.015 |  | 1 | 1452Ppl1096118686/01 | m2 | Plocha podlahy |  | 0.35 | 0.015 | 0 | NEMSOK - Object Layer Attributes #1, Práce: Obklady a dlažby; Object Layer Attributes #1, Materiál: KERAMICKÝ OBKLAD
 | Půdorys 1.NP | CLADDING | KERAMICKÝ OBKLAD 0.015 m | 1 | 0.015 |  | 1 | 1452Spl1096118695/01 | m2 | Plocha stěny |  | 3 | 0.015 | NEMSOK - Object Layer Attributes #1, Práce: Obklady a dlažby; Object Layer Attributes #1, Materiál: KERAMICKÝ OBKLAD; Qto_CoveringBaseQuantities - GrossArea: 3 m2
 | Půdorys 1.NP | FLOORING | KERAMICKÝ OBKLAD 0.015 m | 1 | 0.015 |  | 1 | 1452Ppl1096118696/01 | m2 | Plocha podlahy |  | 0.25 | 0.015 | 0 | NEMSOK - Object Layer Attributes #1, Práce: Obklady a dlažby; Object Layer Attributes #1, Materiál: KERAMICKÝ OBKLAD
 | Půdorys 1.NP | CLADDING | KERAMICKÝ OBKLAD 0.015 m | 1 | 0.015 |  | 1 | 1452Spl1096115692/01 | m2 | Plocha stěny |  | 2.45 | 0.015 | NEMSOK - Object Layer Attributes #1, Práce: Obklady a dlažby; Object Layer Attributes #1, Materiál: KERAMICKÝ OBKLAD; Qto_CoveringBaseQuantities - GrossArea: 2.45 m2
 | Půdorys 1.NP | FLOORING | KERAMICKÝ OBKLAD 0.015 m | 1 | 0.015 |  | 1 | 1452Ppl1096115693/01 | m2 | Plocha podlahy |  | 0.161 | 0.015 | 0 | NEMSOK - Object Layer Attributes #1, Práce: Obklady a dlažby; Object Layer Attributes #1, Materiál: KERAMICKÝ OBKLAD
 | Půdorys 1.NP | CLADDING | KERAMICKÝ OBKLAD 0.015 m | 1 | 0.015 |  | 1 | 1452Spl1096115510/01 | m2 | Plocha stěny |  | 1.155 | 0.015 | NEMSOK - Object Layer Attributes #1, Práce: Obklady a dlažby; Object Layer Attributes #1, Materiál: KERAMICKÝ OBKLAD; Qto_CoveringBaseQuantities - GrossArea: 1.155 m2
 | Půdorys 1.NP | FLOORING | KERAMICKÝ OBKLAD 0.015 m | 1 | 0.015 |  | 1 | 1452Ppl1096115511/01 | m2 | Plocha podlahy |  | 0.266 | 0.015 | 0 | NEMSOK - Object Layer Attributes #1, Práce: Obklady a dlažby; Object Layer Attributes #1, Materiál: KERAMICKÝ OBKLAD
 | Půdorys 1.NP | CLADDING | KERAMICKÝ OBKLAD 0.015 m | 1 | 0.015 |  | 1 | 1452Spl1096115563/01 | m2 | Plocha stěny |  | 0.87 | 0.015 | NEMSOK - Object Layer Attributes #1, Práce: Obklady a dlažby; Object Layer Attributes #1, Materiál: KERAMICKÝ OBKLAD; Qto_CoveringBaseQuantities - GrossArea: 0.915 m2
 | Půdorys 1.NP | FLOORING | KERAMICKÝ OBKLAD 0.015 m | 1 | 0.015 |  | 1 | 1452Ppl1096115564/01 | m2 | Plocha podlahy |  | 0.206 | 0.015 | 0 | NEMSOK - Object Layer Attributes #1, Práce: Obklady a dlažby; Object Layer Attributes #1, Materiál: KERAMICKÝ OBKLAD
 | Půdorys 1.NP | CLADDING | KERAMICKÝ OBKLAD 0.015 m | 1 | 0.015 |  | 1 | 1452Spl1096115616/01 | m2 | Plocha stěny |  | 0.601 | 0.015 | NEMSOK - Object Layer Attributes #1, Práce: Obklady a dlažby; Object Layer Attributes #1, Materiál: KERAMICKÝ OBKLAD; Qto_CoveringBaseQuantities - GrossArea: 0.645 m2
 | Půdorys 1.NP | FLOORING | KERAMICKÝ OBKLAD 0.015 m | 1 | 0.015 |  | 1 | 1452Ppl1096115617/01 | m2 | Plocha podlahy |  | 0.139 | 0.015 | 1 | NEMSOK - Object Layer Attributes #1, Práce: Obklady a dlažby; Object Layer Attributes #1, Materiál: KERAMICKÝ OBKLAD
 | Půdorys 1.NP | CLADDING | KERAMICKÝ OBKLAD 0.015 m | 1 | 0.015 | 0 | 1 | 1464Spl1096159379/01 | m3 | Plocha stěny | NEW | 1.62 | 0.015 | NEMSOK - Object Layer Attributes #1, Kód prvku: OD01.03.0001; Object Layer Attributes #1, Práce: Obklady a dlažby; Object Layer Attributes #1, Materiál: KERAMICKÝ OBKLAD; Object Layer Attributes #1, Podlaží: 1.NP; Object Layer Attributes #1, Způsob položení: flexibilní tmel; Object Layer Attributes #1, Typ hydroizolace: bez; Qto_CoveringBaseQuantities - GrossArea: 1.62 m2
 | Půdorys 1.NP | CLADDING | KERAMICKÝ OBKLAD 0.015 m | 1 | 0.015 | 0 | 1 | 1464Spl1096159439/01 | m3 | Plocha stěny | NEW | 2.124 | 0.015 | NEMSOK - Object Layer Attributes #1, Kód prvku: OD01.03.0002; Object Layer Attributes #1, Práce: Obklady a dlažby; Object Layer Attributes #1, Materiál: KERAMICKÝ OBKLAD; Object Layer Attributes #1, Podlaží: 1.NP; Object Layer Attributes #1, Způsob položení: flexibilní tmel; Object Layer Attributes #1, Typ hydroizolace: bez; Qto_CoveringBaseQuantities - GrossArea: 2.124 m2
 | Půdorys 1.NP | CLADDING | KERAMICKÝ OBKLAD 0.015 m | 1 | 0.015 | 0 | 1 | 1464Spl1096159751/01 | m3 | Plocha stěny | NEW | 1.764 | 0.015 | NEMSOK - Object Layer Attributes #1, Kód prvku: OD01.03.0003; Object Layer Attributes #1, Práce: Obklady a dlažby; Object Layer Attributes #1, Materiál: KERAMICKÝ OBKLAD; Object Layer Attributes #1, Podlaží: 1.NP; Object Layer Attributes #1, Způsob položení: flexibilní tmel; Object Layer Attributes #1, Typ hydroizolace: bez; Qto_CoveringBaseQuantities - GrossArea: 1.764 m2
 | Půdorys 1.NP | CLADDING | KERAMICKÝ OBKLAD 0.015 m | 1 | 0.015 | 0 | 1 | 1464Spl1096177507/01 | m3 | Plocha stěny | NEW | 1.404 | 0.015 | NEMSOK - Object Layer Attributes #1, Kód prvku: OD01.03.0004; Object Layer Attributes #1, Práce: Obklady a dlažby; Object Layer Attributes #1, Materiál: KERAMICKÝ OBKLAD; Object Layer Attributes #1, Podlaží: 1.NP; Object Layer Attributes #1, Způsob položení: flexibilní tmel; Object Layer Attributes #1, Typ hydroizolace: bez; Qto_CoveringBaseQuantities - GrossArea: 1.404 m2
 | Půdorys 1.NP | CLADDING | ACROVINYLOVÝ OBKLAD 0.005 m | 1 | 0.005 | 0 | 1 | 1464Spl1096171675/01 | m3 | Plocha stěny | NEW | 7.254 | 0.005 | NEMSOK - Object Layer Attributes #1, Kód prvku: OD01.05.0001; Object Layer Attributes #1, Práce: Povlakové podlahy; Object Layer Attributes #1, Materiál: ACROVINYLOVÝ OBKLAD; Object Layer Attributes #1, Podlaží: 1.NP; Object Layer Attributes #1, Způsob položení: systémové lepidlo; Object Layer Attributes #1, Typ hydroizolace: bez; Qto_CoveringBaseQuantities - GrossArea: 7.254 m2
 | Půdorys 1.NP | CLADDING | ACROVINYLOVÝ OBKLAD 0.005 m | 1 | 0.005 | 0 | 1 | 1464Spl1096171691/01 | m3 | Plocha stěny | NEW | 10.959 | 0.005 | NEMSOK - Object Layer Attributes #1, Kód prvku: OD01.05.0002; Object Layer Attributes #1, Práce: Povlakové podlahy; Object Layer Attributes #1, Materiál: ACROVINYLOVÝ OBKLAD; Object Layer Attributes #1, Podlaží: 1.NP; Object Layer Attributes #1, Způsob položení: systémové lepidlo; Object Layer Attributes #1, Typ hydroizolace: bez; Qto_CoveringBaseQuantities - GrossArea: 10.959 m2
 | Půdorys 1.NP | FLOORING | SANACE BETONU 0.003 m | 1 | 0.003 | 0 | 1 | 1469Ppl0000003266/01 | m3 | Plocha podlahy | NEW | 0.54 | 0.003 | 7.2 | NEMSOK - Object Layer Attributes #1, Kód prvku: MB05.03.1001; Object Layer Attributes #1, Práce: Potěry a stěrky; Object Layer Attributes #1, Materiál: SANACE BETONU; Object Layer Attributes #1, Podlaží: 1.NP; Object Layer Attributes #1, Způsob provedení: ruční
 | 1.01 | FLOORING | layer 0.095 m, PŘÍRODNÍ LINOLEUM 0.005 m | 1 | 0.095 | 0 | 1 | 1469Ppl0000000351/01 | m3 | Plocha podlahy | NEW | 48.806 | 0.1 | 0 | NEMSOK - Object Layer Attributes #2, Status: Nový; Object Layer Attributes #2, Kód prvku: PD06.03.0001; Object Layer Attributes #2, Práce: Povlakové podlahy; Object Layer Attributes #2, Číslo_vrstvy: 2; Object Layer Attributes #2, Tloušťka_vrstvy: 0.005 m; Object Layer Attributes #2, Tloušťka: 0 m; Object Layer Attributes #2, Faktor: 1; Object Layer Attributes #2, Označení: II.P4; Object Layer Attributes #2, Materiál: PŘÍRODNÍ LINOLEUM; Object Layer Attributes #2, Vztažná_výška: 0; Object Layer Attributes #2, Delta_výšky: 0; Object Layer Attributes #2, Podlaží: 1.NP; Object Layer Attributes #2, Číslo místnosti: 1.01; Object Layer Attributes #2, Plošná únosnost: 3; Object Layer Attributes #2, Allright_Stavebni_dil_ID: 1469Ppl0000000351/02; Object Layer Attributes #2, Jednotka: m3; Object Layer Attributes #2, Název_objektu: Plocha podlahy; Object Layer Attributes #2, Kročejová neprůzvučnost: 58
 | 1.01 | SKIRTINGBOARD | FABION |  |  |  |  |  |  |  | NEW | NEMSOK - Kód prvku: PD00.03.0000; Práce: Povlakové podlahy; Faktor: 1; Materiál: FABION; Vztažná_výška: 0; Delta_výšky: 0; Allright_Stavebni_dil_ID: 1469Liš0000002863; Jednotka: m; Název_objektu: Lišta
 | 1.01 | CEILING | RASTR 1 0.03 m | 1 | 0.03 | 0 | 1 | 1469Dpl0000000350/01 | m3 | Plocha stropu | NEW | 48.806 | 0.03 | 0 | NEMSOK - Object Layer Attributes #1, Kód prvku: PH03.03.1001; Object Layer Attributes #1, Práce: Suché stavební práce; Object Layer Attributes #1, Materiál: RASTR 1; Object Layer Attributes #1, Výška svěšení: 0.6 m; Object Layer Attributes #1, Únosnost bodová: 0.5 kg; Pset_CoveringCommon - Flammability: bez požadavku
 | K1.09 | FLOORING | layer 0.285 m, KERAMICKÁ DLAŽBA 0.015 m | 1 | 0.285 | 0 | 1 | 1469Ppl0000000430/01 | m3 | Plocha podlahy | NEW | 19.335 | 0.3 | 0 | NEMSOK - Object Layer Attributes #2, Status: Nový; Object Layer Attributes #2, Kód prvku: PD01.03.0001; Object Layer Attributes #2, Práce: Obklady a dlažby; Object Layer Attributes #2, Číslo_vrstvy: 2; Object Layer Attributes #2, Tloušťka_vrstvy: 0.015 m; Object Layer Attributes #2, Tloušťka: 0 m; Object Layer Attributes #2, Faktor: 1; Object Layer Attributes #2, Označení: II.P2; Object Layer Attributes #2, Materiál: KERAMICKÁ DLAŽBA; Object Layer Attributes #2, Vztažná_výška: 0; Object Layer Attributes #2, Delta_výšky: 0; Object Layer Attributes #2, Podlaží: 1.NP; Object Layer Attributes #2, Číslo místnosti: K1.09; Object Layer Attributes #2, Plošná únosnost: 5; Object Layer Attributes #2, Allright_Stavebni_dil_ID: 1469Ppl0000000430/02; Object Layer Attributes #2, Jednotka: m3; Object Layer Attributes #2, Název_objektu: Plocha podlahy
 | K1.09 | SKIRTINGBOARD | SOKLOVÁ PVC LIŠTA |  |  |  |  |  |  |  | NEW | NEMSOK - Kód prvku: PD00.03.0000; Práce: Povlakové podlahy; Faktor: 1; Materiál: SOKLOVÁ PVC LIŠTA; Vztažná_výška: 0; Delta_výšky: 0; Allright_Stavebni_dil_ID: 1469Liš0000002853; Jednotka: m; Název_objektu: Lišta
 | K1.09 | CEILING | RASTR 1 0.03 m | 1 | 0.03 | 0 | 1 | 1469Dpl0000000429/01 | m3 | Plocha stropu | NEW | 19.335 | 0.03 | 0 | NEMSOK - Object Layer Attributes #1, Kód prvku: PH03.03.1001; Object Layer Attributes #1, Práce: Suché stavební práce; Object Layer Attributes #1, Materiál: RASTR 1; Object Layer Attributes #1, Výška svěšení: 0.6 m; Object Layer Attributes #1, Únosnost bodová: 0.5 kg; Pset_CoveringCommon - Flammability: bez požadavku
 | K1.10 | FLOORING | layer 0.285 m, KERAMICKÁ DLAŽBA 0.015 m | 1 | 0.285 | 0 | 1 | 1469Ppl0000000442/01 | m3 | Plocha podlahy | NEW | 6.919 | 0.3 | 0 | NEMSOK - Object Layer Attributes #2, Status: Nový; Object Layer Attributes #2, Kód prvku: PD01.03.0001; Object Layer Attributes #2, Práce: Obklady a dlažby; Object Layer Attributes #2, Číslo_vrstvy: 2; Object Layer Attributes #2, Tloušťka_vrstvy: 0.015 m; Object Layer Attributes #2, Tloušťka: 0 m; Object Layer Attributes #2, Faktor: 1; Object Layer Attributes #2, Označení: II.P2; Object Layer Attributes #2, Materiál: KERAMICKÁ DLAŽBA; Object Layer Attributes #2, Vztažná_výška: 0; Object Layer Attributes #2, Delta_výšky: 0; Object Layer Attributes #2, Podlaží: 1.NP; Object Layer Attributes #2, Číslo místnosti: K1.10; Object Layer Attributes #2, Plošná únosnost: 5; Object Layer Attributes #2, Allright_Stavebni_dil_ID: 1469Ppl0000000442/02; Object Layer Attributes #2, Jednotka: m3; Object Layer Attributes #2, Název_objektu: Plocha podlahy
 | K1.10 | SKIRTINGBOARD | SOKLOVÁ PVC LIŠTA |  |  |  |  |  |  |  | NEW | NEMSOK - Kód prvku: PD00.03.0000; Práce: Povlakové podlahy; Faktor: 1; Materiál: SOKLOVÁ PVC LIŠTA; Vztažná_výška: 0; Delta_výšky: 0; Allright_Stavebni_dil_ID: 1469Liš0000002854; Jednotka: m; Název_objektu: Lišta
 | K1.10 | CEILING | RASTR 2 0.03 m | 1 | 0.03 | 0 | 1 | 1469Dpl0000000441/01 | m3 | Plocha stropu | NEW | 6.919 | 0.03 | 0 | NEMSOK - Object Layer Attributes #1, Kód prvku: PH03.03.2001; Object Layer Attributes #1, Práce: Suché stavební práce; Object Layer Attributes #1, Materiál: RASTR 2; Object Layer Attributes #1, Výška svěšení: 0.6 m; Object Layer Attributes #1, Únosnost bodová: 0.5 kg; Pset_CoveringCommon - Flammability: bez požadavku
 | K1.12 | FLOORING | layer 0.285 m, KERAMICKÁ DLAŽBA 0.015 m | 1 | 0.285 | 0 | 1 | 1469Ppl0000000451/01 | m3 | Plocha podlahy | NEW | 2.031 | 0.3 | 0 | NEMSOK - Object Layer Attributes #2, Status: Nový; Object Layer Attributes #2, Kód prvku: PD01.03.0001; Object Layer Attributes #2, Práce: Obklady a dlažby; Object Layer Attributes #2, Číslo_vrstvy: 2; Object Layer Attributes #2, Tloušťka_vrstvy: 0.015 m; Object Layer Attributes #2, Tloušťka: 0 m; Object Layer Attributes #2, Faktor: 1; Object Layer Attributes #2, Označení: II.P2; Object Layer Attributes #2, Materiál: KERAMICKÁ DLAŽBA; Object Layer Attributes #2, Vztažná_výška: 0; Object Layer Attributes #2, Delta_výšky: 0; Object Layer Attributes #2, Podlaží: 1.NP; Object Layer Attributes #2, Číslo místnosti: K1.12; Object Layer Attributes #2, Plošná únosnost: 5; Object Layer Attributes #2, Allright_Stavebni_dil_ID: 1469Ppl0000000451/02; Object Layer Attributes #2, Jednotka: m3; Object Layer Attributes #2, Název_objektu: Plocha podlahy
 | K1.12 | CEILING | RASTR 2 0.03 m | 1 | 0.03 | 0 | 1 | 1469Dpl0000000450/01 | m3 | Plocha stropu | NEW | 2.031 | 0.03 | 0 | NEMSOK - Object Layer Attributes #1, Kód prvku: PH03.03.2001; Object Layer Attributes #1, Práce: Suché stavební práce; Object Layer Attributes #1, Materiál: RASTR 2; Object Layer Attributes #1, Výška svěšení: 0.6 m; Object Layer Attributes #1, Únosnost bodová: 0.5 kg; Pset_CoveringCommon - Flammability: bez požadavku
 | K1.11 | FLOORING | layer 0.285 m, KERAMICKÁ DLAŽBA 0.015 m | 1 | 0.285 | 0 | 1 | 1469Ppl0000000462/01 | m3 | Plocha podlahy | NEW | 5.025 | 0.3 | 0 | NEMSOK - Object Layer Attributes #2, Status: Nový; Object Layer Attributes #2, Kód prvku: PD01.03.0001; Object Layer Attributes #2, Práce: Obklady a dlažby; Object Layer Attributes #2, Číslo_vrstvy: 2; Object Layer Attributes #2, Tloušťka_vrstvy: 0.015 m; Object Layer Attributes #2, Tloušťka: 0 m; Object Layer Attributes #2, Faktor: 1; Object Layer Attributes #2, Označení: II.P2; Object Layer Attributes #2, Materiál: KERAMICKÁ DLAŽBA; Object Layer Attributes #2, Vztažná_výška: 0; Object Layer Attributes #2, Delta_výšky: 0; Object Layer Attributes #2, Podlaží: 1.NP; Object Layer Attributes #2, Číslo místnosti: K1.11; Object Layer Attributes #2, Plošná únosnost: 5; Object Layer Attributes #2, Allright_Stavebni_dil_ID: 1469Ppl0000000462/02; Object Layer Attributes #2, Jednotka: m3; Object Layer Attributes #2, Název_objektu: Plocha podlahy
 | K1.11 | SKIRTINGBOARD | SOKLOVÁ PVC LIŠTA |  |  |  |  |  |  |  | NEW | NEMSOK - Kód prvku: PD00.03.0000; Práce: Povlakové podlahy; Faktor: 1; Materiál: SOKLOVÁ PVC LIŠTA; Vztažná_výška: 0; Delta_výšky: 0; Allright_Stavebni_dil_ID: 1469Liš0000002856; Jednotka: m; Název_objektu: Lišta
 | K1.11 | CEILING | RASTR 2 0.03 m | 1 | 0.03 | 0 | 1 | 1469Dpl0000000461/01 | m3 | Plocha stropu | NEW | 5.025 | 0.03 | 0 | NEMSOK - Object Layer Attributes #1, Kód prvku: PH03.03.2001; Object Layer Attributes #1, Práce: Suché stavební práce; Object Layer Attributes #1, Materiál: RASTR 2; Object Layer Attributes #1, Výška svěšení: 0.6 m; Object Layer Attributes #1, Únosnost bodová: 0.5 kg; Pset_CoveringCommon - Flammability: bez požadavku
 | K1.13 | FLOORING | layer 0.285 m, KERAMICKÁ DLAŽBA 0.015 m | 1 | 0.285 | 0 | 1 | 1469Ppl0000000473/01 | m3 | Plocha podlahy | NEW | 3.5 | 0.3 | 0 | NEMSOK - Object Layer Attributes #2, Status: Nový; Object Layer Attributes #2, Kód prvku: PD01.03.0001; Object Layer Attributes #2, Práce: Obklady a dlažby; Object Layer Attributes #2, Číslo_vrstvy: 2; Object Layer Attributes #2, Tloušťka_vrstvy: 0.015 m; Object Layer Attributes #2, Tloušťka: 0 m; Object Layer Attributes #2, Faktor: 1; Object Layer Attributes #2, Označení: II.P2; Object Layer Attributes #2, Materiál: KERAMICKÁ DLAŽBA; Object Layer Attributes #2, Vztažná_výška: 0; Object Layer Attributes #2, Delta_výšky: 0; Object Layer Attributes #2, Podlaží: 1.NP; Object Layer Attributes #2, Číslo místnosti: K1.13; Object Layer Attributes #2, Plošná únosnost: 5; Object Layer Attributes #2, Allright_Stavebni_dil_ID: 1469Ppl0000000473/02; Object Layer Attributes #2, Jednotka: m3; Object Layer Attributes #2, Název_objektu: Plocha podlahy
 | K1.13 | SKIRTINGBOARD | SOKLOVÁ PVC LIŠTA |  |  |  |  |  |  |  | NEW | NEMSOK - Kód prvku: PD00.03.0000; Práce: Povlakové podlahy; Faktor: 1; Materiál: SOKLOVÁ PVC LIŠTA; Vztažná_výška: 0; Delta_výšky: 0; Allright_Stavebni_dil_ID: 1469Liš0000002855; Jednotka: m; Název_objektu: Lišta
 | K1.13 | CEILING | RASTR 2 0.03 m | 1 | 0.03 | 0 | 1 | 1469Dpl0000000472/01 | m3 | Plocha stropu | NEW | 3.5 | 0.03 | 0 | NEMSOK - Object Layer Attributes #1, Kód prvku: PH03.03.2001; Object Layer Attributes #1, Práce: Suché stavební práce; Object Layer Attributes #1, Materiál: RASTR 2; Object Layer Attributes #1, Výška svěšení: 0.6 m; Object Layer Attributes #1, Únosnost bodová: 0.5 kg; Pset_CoveringCommon - Flammability: bez požadavku
 | K1.14a | FLOORING | layer 0.285 m, KERAMICKÁ DLAŽBA 0.015 m | 1 | 0.285 | 0 | 1 | 1469Ppl0000000484/01 | m3 | Plocha podlahy | NEW | 1.327 | 0.3 | 0 | NEMSOK - Object Layer Attributes #2, Status: Nový; Object Layer Attributes #2, Kód prvku: PD01.03.0001; Object Layer Attributes #2, Práce: Obklady a dlažby; Object Layer Attributes #2, Číslo_vrstvy: 2; Object Layer Attributes #2, Tloušťka_vrstvy: 0.015 m; Object Layer Attributes #2, Tloušťka: 0 m; Object Layer Attributes #2, Faktor: 1; Object Layer Attributes #2, Označení: II.P2; Object Layer Attributes #2, Materiál: KERAMICKÁ DLAŽBA; Object Layer Attributes #2, Vztažná_výška: 0; Object Layer Attributes #2, Delta_výšky: 0; Object Layer Attributes #2, Podlaží: 1.NP; Object Layer Attributes #2, Číslo místnosti: K1.14a; Object Layer Attributes #2, Plošná únosnost: 5; Object Layer Attributes #2, Allright_Stavebni_dil_ID: 1469Ppl0000000484/02; Object Layer Attributes #2, Jednotka: m3; Object Layer Attributes #2, Název_objektu: Plocha podlahy
 | K1.14a | CEILING | RASTR 2 0.03 m | 1 | 0.03 | 0 | 1 | 1469Dpl0000000483/01 | m3 | Plocha stropu | NEW | 1.327 | 0.03 | 0 | NEMSOK - Object Layer Attributes #1, Kód prvku: PH03.03.2001; Object Layer Attributes #1, Práce: Suché stavební práce; Object Layer Attributes #1, Materiál: RASTR 2; Object Layer Attributes #1, Výška svěšení: 0.6 m; Object Layer Attributes #1, Únosnost bodová: 0.5 kg; Pset_CoveringCommon - Flammability: bez požadavku
 | K1.14 | FLOORING | layer 0.285 m, KERAMICKÁ DLAŽBA 0.015 m | 1 | 0.285 | 0 | 1 | 1469Ppl0000000493/01 | m3 | Plocha podlahy | NEW | 3.631 | 0.3 | 0 | NEMSOK - Object Layer Attributes #2, Status: Nový; Object Layer Attributes #2, Kód prvku: PD01.03.0001; Object Layer Attributes #2, Práce: Obklady a dlažby; Object Layer Attributes #2, Číslo_vrstvy: 2; Object Layer Attributes #2, Tloušťka_vrstvy: 0.015 m; Object Layer Attributes #2, Tloušťka: 0 m; Object Layer Attributes #2, Faktor: 1; Object Layer Attributes #2, Označení: II.P2; Object Layer Attributes #2, Materiál: KERAMICKÁ DLAŽBA; Object Layer Attributes #2, Vztažná_výška: 0; Object Layer Attributes #2, Delta_výšky: 0; Object Layer Attributes #2, Podlaží: 1.NP; Object Layer Attributes #2, Číslo místnosti: K1.14; Object Layer Attributes #2, Plošná únosnost: 5; Object Layer Attributes #2, Allright_Stavebni_dil_ID: 1469Ppl0000000493/02; Object Layer Attributes #2, Jednotka: m3; Object Layer Attributes #2, Název_objektu: Plocha podlahy
 | K1.14 | CEILING | RASTR 2 0.03 m | 1 | 0.03 | 0 | 1 | 1469Dpl0000000492/01 | m3 | Plocha stropu | NEW | 3.631 | 0.03 | 0 | NEMSOK - Object Layer Attributes #1, Kód prvku: PH03.03.2001; Object Layer Attributes #1, Práce: Suché stavební práce; Object Layer Attributes #1, Materiál: RASTR 2; Object Layer Attributes #1, Výška svěšení: 0.6 m; Object Layer Attributes #1, Únosnost bodová: 0.5 kg; Pset_CoveringCommon - Flammability: bez požadavku
 | K1.01 | FLOORING | layer 0.095 m, AKUSTICKÝ VINYL 0.005 m | 1 | 0.095 | 0 | 1 | 1469Ppl0000000530/01 | m3 | Plocha podlahy | NEW | 10.694 | 0.1 | 0 | NEMSOK - Object Layer Attributes #2, Status: Nový; Object Layer Attributes #2, Kód prvku: PD06.03.2001; Object Layer Attributes #2, Práce: Povlakové podlahy; Object Layer Attributes #2, Číslo_vrstvy: 2; Object Layer Attributes #2, Tloušťka_vrstvy: 0.005 m; Object Layer Attributes #2, Tloušťka: 0 m; Object Layer Attributes #2, Faktor: 1; Object Layer Attributes #2, Označení: II.P3; Object Layer Attributes #2, Materiál: AKUSTICKÝ VINYL; Object Layer Attributes #2, Vztažná_výška: 0; Object Layer Attributes #2, Delta_výšky: 0; Object Layer Attributes #2, Podlaží: 1.NP; Object Layer Attributes #2, Číslo místnosti: K1.01; Object Layer Attributes #2, Plošná únosnost: 3; Object Layer Attributes #2, Allright_Stavebni_dil_ID: 1469Ppl0000000530/02; Object Layer Attributes #2, Jednotka: m3; Object Layer Attributes #2, Název_objektu: Plocha podlahy; Object Layer Attributes #2, Kročejová neprůzvučnost: 54.5
 | K1.01 | CEILING | MALBA 0.005 m, SDK PODHLED 0.025 m | 1 | 0.005 | 0 | 1 | 1469Dpl0000000529/01 | m3 | Plocha stropu | NEW | 10.694 | 0.03 | 0 | NEMSOK - Object Layer Attributes #1, Kód prvku: MB03.03.1001; Object Layer Attributes #1, Práce: Malby a nátěry; Object Layer Attributes #1, Materiál: MALBA; Object Layer Attributes #1, Podlaží: 1.NP; Object Layer Attributes #1, Způsob provedení: ruční; Object Layer Attributes #2, Status: Nový; Object Layer Attributes #2, Kód prvku: PH01.03.0001; Object Layer Attributes #2, Práce: Suché stavební práce; Object Layer Attributes #2, Číslo_vrstvy: 2; Object Layer Attributes #2, Tloušťka_vrstvy: 0.025 m; Object Layer Attributes #2, Tloušťka: 0 m; Object Layer Attributes #2, Faktor: 1; Object Layer Attributes #2, Materiál: SDK PODHLED; Object Layer Attributes #2, Vztažná_výška: 0; Object Layer Attributes #2, Delta_výšky: 0; Object Layer Attributes #2, Allright_Stavebni_dil_ID: 1469Dpl0000000529/02; Object Layer Attributes #2, Jednotka: m3; Object Layer Attributes #2, Název_objektu: Plocha stropu; Object Layer Attributes #2, Požární odolnost: bez požadavku; Object Layer Attributes #2, Výška svěšení: 0.6 m; Object Layer Attributes #2, Únosnost bodová: 0.5 kg
 | K1.01 | SKIRTINGBOARD | SOKLOVÁ PVC LIŠTA |  |  |  |  |  |  |  | NEW | NEMSOK - Kód prvku: PD00.03.0000; Práce: Povlakové podlahy; Faktor: 1; Materiál: SOKLOVÁ PVC LIŠTA; Vztažná_výška: 0; Delta_výšky: 0; Allright_Stavebni_dil_ID: 1469Liš0000002861; Jednotka: m; Název_objektu: Lišta
 | K1.02 | FLOORING | layer 0.085 m, KERAMICKÁ DLAŽBA 0.015 m | 1 | 0.085 | 0 | 1 | 1469Ppl0000000541/01 | m3 | Plocha podlahy | NEW | 2.219 | 0.1 | 0 | NEMSOK - Object Layer Attributes #2, Status: Nový; Object Layer Attributes #2, Kód prvku: PD01.03.0001; Object Layer Attributes #2, Práce: Obklady a dlažby; Object Layer Attributes #2, Číslo_vrstvy: 2; Object Layer Attributes #2, Tloušťka_vrstvy: 0.015 m; Object Layer Attributes #2, Tloušťka: 0 m; Object Layer Attributes #2, Faktor: 1; Object Layer Attributes #2, Označení: II.P5; Object Layer Attributes #2, Materiál: KERAMICKÁ DLAŽBA; Object Layer Attributes #2, Vztažná_výška: 0; Object Layer Attributes #2, Delta_výšky: 0; Object Layer Attributes #2, Podlaží: 1.NP; Object Layer Attributes #2, Číslo místnosti: K1.02; Object Layer Attributes #2, Plošná únosnost: 3; Object Layer Attributes #2, Allright_Stavebni_dil_ID: 1469Ppl0000000541/02; Object Layer Attributes #2, Jednotka: m3; Object Layer Attributes #2, Název_objektu: Plocha podlahy; Object Layer Attributes #2, Kročejová neprůzvučnost: 54.5
 | K1.02 | SKIRTINGBOARD | SOKLOVÁ PVC LIŠTA |  |  |  |  |  |  |  | NEW | NEMSOK - Kód prvku: PD00.03.0000; Práce: Povlakové podlahy; Faktor: 1; Materiál: SOKLOVÁ PVC LIŠTA; Vztažná_výška: 0; Delta_výšky: 0; Allright_Stavebni_dil_ID: 1469Liš0000002860; Jednotka: m; Název_objektu: Lišta
 | K1.02 | CEILING | RASTR 2 0.03 m | 1 | 0.03 | 0 | 1 | 1469Dpl0000000540/01 | m3 | Plocha stropu | NEW | 2.219 | 0.03 | 0 | NEMSOK - Object Layer Attributes #1, Kód prvku: PH03.03.2001; Object Layer Attributes #1, Práce: Suché stavební práce; Object Layer Attributes #1, Materiál: RASTR 2; Object Layer Attributes #1, Výška svěšení: 0.6 m; Object Layer Attributes #1, Únosnost bodová: 0.5 kg; Pset_CoveringCommon - Flammability: bez požadavku
 | K1.03 | FLOORING | layer 0.085 m, KERAMICKÁ DLAŽBA 0.015 m | 1 | 0.085 | 0 | 1 | 1469Ppl0000000552/01 | m3 | Plocha podlahy | NEW | 2.275 | 0.1 | 0 | NEMSOK - Object Layer Attributes #2, Status: Nový; Object Layer Attributes #2, Kód prvku: PD01.03.0001; Object Layer Attributes #2, Práce: Obklady a dlažby; Object Layer Attributes #2, Číslo_vrstvy: 2; Object Layer Attributes #2, Tloušťka_vrstvy: 0.015 m; Object Layer Attributes #2, Tloušťka: 0 m; Object Layer Attributes #2, Faktor: 1; Object Layer Attributes #2, Označení: II.P5; Object Layer Attributes #2, Materiál: KERAMICKÁ DLAŽBA; Object Layer Attributes #2, Vztažná_výška: 0; Object Layer Attributes #2, Delta_výšky: 0; Object Layer Attributes #2, Podlaží: 1.NP; Object Layer Attributes #2, Číslo místnosti: K1.03; Object Layer Attributes #2, Plošná únosnost: 3; Object Layer Attributes #2, Allright_Stavebni_dil_ID: 1469Ppl0000000552/02; Object Layer Attributes #2, Jednotka: m3; Object Layer Attributes #2, Název_objektu: Plocha podlahy; Object Layer Attributes #2, Kročejová neprůzvučnost: 54.5
 | K1.03 | SKIRTINGBOARD | SOKLOVÁ PVC LIŠTA |  |  |  |  |  |  |  | NEW | NEMSOK - Kód prvku: PD00.03.0000; Práce: Povlakové podlahy; Faktor: 1; Materiál: SOKLOVÁ PVC LIŠTA; Vztažná_výška: 0; Delta_výšky: 0; Allright_Stavebni_dil_ID: 1469Liš0000002859; Jednotka: m; Název_objektu: Lišta
 | K1.03 | CEILING | RASTR 2 0.03 m | 1 | 0.03 | 0 | 1 | 1469Dpl0000000551/01 | m3 | Plocha stropu | NEW | 2.275 | 0.03 | 0 | NEMSOK - Object Layer Attributes #1, Kód prvku: PH03.03.2001; Object Layer Attributes #1, Práce: Suché stavební práce; Object Layer Attributes #1, Materiál: RASTR 2; Object Layer Attributes #1, Výška svěšení: 0.6 m; Object Layer Attributes #1, Únosnost bodová: 0.5 kg; Pset_CoveringCommon - Flammability: bez požadavku
 | K1.06 | FLOORING | layer 0.095 m, PŘÍRODNÍ LINOLEUM 0.005 m | 1 | 0.095 | 0 | 1 | 1469Ppl0000000561/01 | m3 | Plocha podlahy | NEW | 5.012 | 0.1 | 0 | NEMSOK - Object Layer Attributes #2, Status: Nový; Object Layer Attributes #2, Kód prvku: PD06.03.0001; Object Layer Attributes #2, Práce: Povlakové podlahy; Object Layer Attributes #2, Číslo_vrstvy: 2; Object Layer Attributes #2, Tloušťka_vrstvy: 0.005 m; Object Layer Attributes #2, Tloušťka: 0 m; Object Layer Attributes #2, Faktor: 1; Object Layer Attributes #2, Označení: II.P4; Object Layer Attributes #2, Materiál: PŘÍRODNÍ LINOLEUM; Object Layer Attributes #2, Vztažná_výška: 0; Object Layer Attributes #2, Delta_výšky: 0; Object Layer Attributes #2, Podlaží: 1.NP; Object Layer Attributes #2, Číslo místnosti: K1.06; Object Layer Attributes #2, Plošná únosnost: 3; Object Layer Attributes #2, Allright_Stavebni_dil_ID: 1469Ppl0000000561/02; Object Layer Attributes #2, Jednotka: m3; Object Layer Attributes #2, Název_objektu: Plocha podlahy; Object Layer Attributes #2, Kročejová neprůzvučnost: 54.5
 | K1.06 | SKIRTINGBOARD | SOKLOVÁ PVC LIŠTA |  |  |  |  |  |  |  | NEW | NEMSOK - Kód prvku: PD00.03.0000; Práce: Povlakové podlahy; Faktor: 1; Materiál: SOKLOVÁ PVC LIŠTA; Vztažná_výška: 0; Delta_výšky: 0; Allright_Stavebni_dil_ID: 1469Liš0000002862; Jednotka: m; Název_objektu: Lišta
 | K1.06 | CEILING | RASTR 2 0.03 m | 1 | 0.03 | 0 | 1 | 1469Dpl0000000560/01 | m3 | Plocha stropu | NEW | 5.012 | 0.03 | 0 | NEMSOK - Object Layer Attributes #1, Kód prvku: PH03.03.2001; Object Layer Attributes #1, Práce: Suché stavební práce; Object Layer Attributes #1, Materiál: RASTR 2; Object Layer Attributes #1, Výška svěšení: 0.6 m; Object Layer Attributes #1, Únosnost bodová: 0.5 kg; Pset_CoveringCommon - Flammability: bez požadavku
 | K1.04 | FLOORING | layer 0.085 m, KERAMICKÁ DLAŽBA 0.015 m | 1 | 0.085 | 0 | 1 | 1469Ppl0000000572/01 | m3 | Plocha podlahy | NEW | 2.345 | 0.1 | 0 | NEMSOK - Object Layer Attributes #2, Status: Nový; Object Layer Attributes #2, Kód prvku: PD01.03.0001; Object Layer Attributes #2, Práce: Obklady a dlažby; Object Layer Attributes #2, Číslo_vrstvy: 2; Object Layer Attributes #2, Tloušťka_vrstvy: 0.015 m; Object Layer Attributes #2, Tloušťka: 0 m; Object Layer Attributes #2, Faktor: 1; Object Layer Attributes #2, Označení: II.P5; Object Layer Attributes #2, Materiál: KERAMICKÁ DLAŽBA; Object Layer Attributes #2, Vztažná_výška: 0; Object Layer Attributes #2, Delta_výšky: 0; Object Layer Attributes #2, Podlaží: 1.NP; Object Layer Attributes #2, Číslo místnosti: K1.04; Object Layer Attributes #2, Plošná únosnost: 3; Object Layer Attributes #2, Allright_Stavebni_dil_ID: 1469Ppl0000000572/02; Object Layer Attributes #2, Jednotka: m3; Object Layer Attributes #2, Název_objektu: Plocha podlahy; Object Layer Attributes #2, Kročejová neprůzvučnost: 54.5
 | K1.04 | CEILING | MALBA 0.005 m, SDK PODHLED 0.025 m | 1 | 0.005 | 0 | 1 | 1469Dpl0000000571/01 | m3 | Plocha stropu | NEW | 2.345 | 0.03 | 0 | NEMSOK - Object Layer Attributes #1, Kód prvku: MB03.03.1001; Object Layer Attributes #1, Práce: Malby a nátěry; Object Layer Attributes #1, Materiál: MALBA; Object Layer Attributes #1, Podlaží: 1.NP; Object Layer Attributes #1, Způsob provedení: ruční; Object Layer Attributes #2, Status: Nový; Object Layer Attributes #2, Kód prvku: PH01.03.0001; Object Layer Attributes #2, Práce: Suché stavební práce; Object Layer Attributes #2, Číslo_vrstvy: 2; Object Layer Attributes #2, Tloušťka_vrstvy: 0.025 m; Object Layer Attributes #2, Tloušťka: 0 m; Object Layer Attributes #2, Faktor: 1; Object Layer Attributes #2, Materiál: SDK PODHLED; Object Layer Attributes #2, Vztažná_výška: 0; Object Layer Attributes #2, Delta_výšky: 0; Object Layer Attributes #2, Allright_Stavebni_dil_ID: 1469Dpl0000000571/02; Object Layer Attributes #2, Jednotka: m3; Object Layer Attributes #2, Název_objektu: Plocha stropu; Object Layer Attributes #2, Požární odolnost: bez požadavku; Object Layer Attributes #2, Výška svěšení: 0.6 m; Object Layer Attributes #2, Únosnost bodová: 0.5 kg
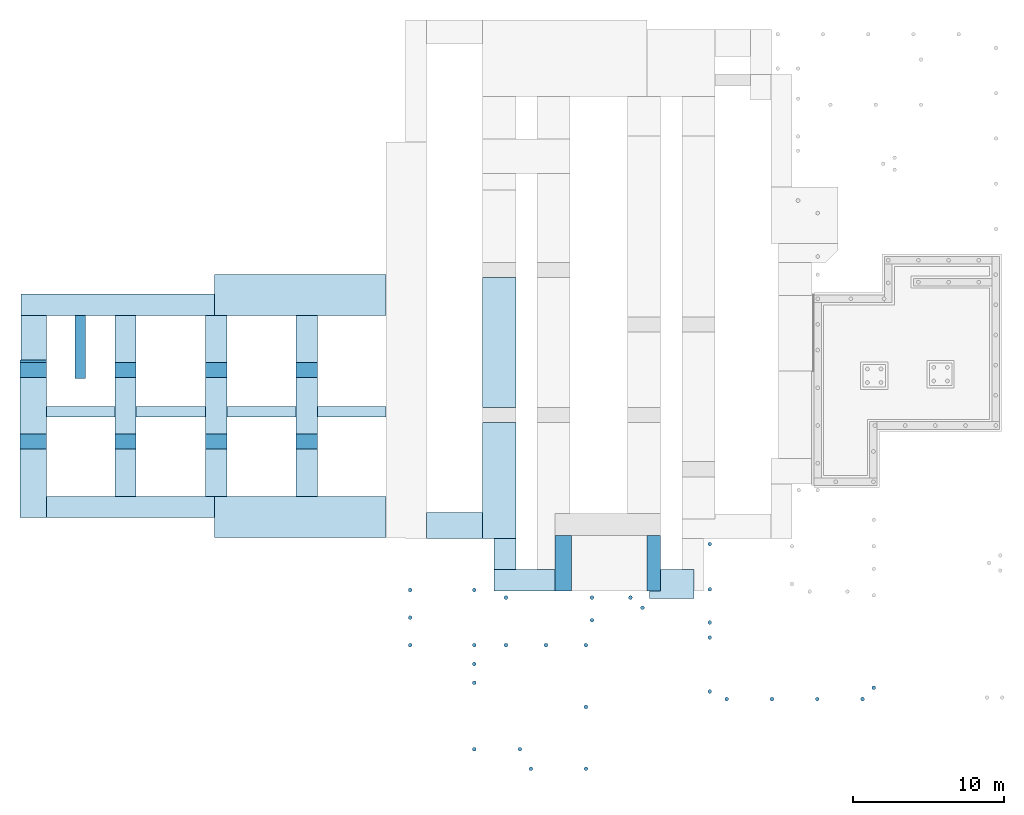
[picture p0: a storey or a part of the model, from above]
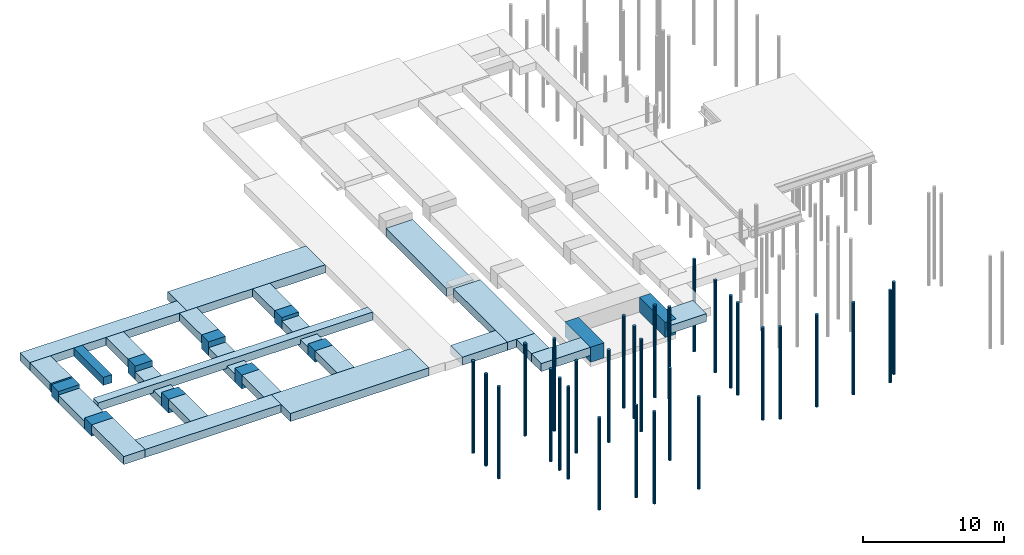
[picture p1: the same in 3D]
Properties of the parts of a building model (IFC4), part 7 of 45

# IfcCovering (314)
Name | In | PredefinedType | Material | Object Layer Attributes #1, Číslo_vrstvy | Object Layer Attributes #1, Tloušťka_vrstvy (m) | Object Layer Attributes #1, Tloušťka (m) = Object Layer Attributes #1, Vztažná_výška = Object Layer Attributes #1, Delta_výšky | Object Layer Attributes #1, Faktor | Object Layer Attributes #1, Allright_Stavebni_dil_ID | Object Layer Attributes #1, Jednotka | Object Layer Attributes #1, Název_objektu | Status | NetArea (m2) | Width (m) | Perimeter (m)
 | K1.05 | FLOORING | layer 0.085 m, KERAMICKÁ DLAŽBA 0.015 m | 1 | 0.085 | 0 | 1 | 1469Ppl0000000583/01 | m3 | Plocha podlahy | NEW | 4.236 | 0.1 | 0 | NEMSOK - Object Layer Attributes #2, Status: Nový; Object Layer Attributes #2, Kód prvku: PD01.03.0001; Object Layer Attributes #2, Práce: Obklady a dlažby; Object Layer Attributes #2, Číslo_vrstvy: 2; Object Layer Attributes #2, Tloušťka_vrstvy: 0.015 m; Object Layer Attributes #2, Tloušťka: 0 m; Object Layer Attributes #2, Faktor: 1; Object Layer Attributes #2, Označení: II.P5; Object Layer Attributes #2, Materiál: KERAMICKÁ DLAŽBA; Object Layer Attributes #2, Vztažná_výška: 0; Object Layer Attributes #2, Delta_výšky: 0; Object Layer Attributes #2, Podlaží: 1.NP; Object Layer Attributes #2, Číslo místnosti: K1.05; Object Layer Attributes #2, Plošná únosnost: 3; Object Layer Attributes #2, Allright_Stavebni_dil_ID: 1469Ppl0000000583/02; Object Layer Attributes #2, Jednotka: m3; Object Layer Attributes #2, Název_objektu: Plocha podlahy; Object Layer Attributes #2, Kročejová neprůzvučnost: 54.5
 | K1.05 | CEILING | MALBA 0.005 m, SDK PODHLED 0.025 m | 1 | 0.005 | 0 | 1 | 1469Dpl0000000582/01 | m3 | Plocha stropu | NEW | 4.236 | 0.03 | 0 | NEMSOK - Object Layer Attributes #1, Kód prvku: MB03.03.1001; Object Layer Attributes #1, Práce: Malby a nátěry; Object Layer Attributes #1, Materiál: MALBA; Object Layer Attributes #1, Podlaží: 1.NP; Object Layer Attributes #1, Způsob provedení: ruční; Object Layer Attributes #2, Status: Nový; Object Layer Attributes #2, Kód prvku: PH01.03.0001; Object Layer Attributes #2, Práce: Suché stavební práce; Object Layer Attributes #2, Číslo_vrstvy: 2; Object Layer Attributes #2, Tloušťka_vrstvy: 0.025 m; Object Layer Attributes #2, Tloušťka: 0 m; Object Layer Attributes #2, Faktor: 1; Object Layer Attributes #2, Materiál: SDK PODHLED; Object Layer Attributes #2, Vztažná_výška: 0; Object Layer Attributes #2, Delta_výšky: 0; Object Layer Attributes #2, Allright_Stavebni_dil_ID: 1469Dpl0000000582/02; Object Layer Attributes #2, Jednotka: m3; Object Layer Attributes #2, Název_objektu: Plocha stropu; Object Layer Attributes #2, Požární odolnost: bez požadavku; Object Layer Attributes #2, Výška svěšení: 0.6 m; Object Layer Attributes #2, Únosnost bodová: 0.5 kg
 | K1.04a | FLOORING | layer 0.085 m, KERAMICKÁ DLAŽBA 0.015 m | 1 | 0.085 | 0 | 1 | 1469Ppl0000000592/01 | m3 | Plocha podlahy | NEW | 1.575 | 0.1 | 0 | NEMSOK - Object Layer Attributes #2, Status: Nový; Object Layer Attributes #2, Kód prvku: PD01.03.0001; Object Layer Attributes #2, Práce: Obklady a dlažby; Object Layer Attributes #2, Číslo_vrstvy: 2; Object Layer Attributes #2, Tloušťka_vrstvy: 0.015 m; Object Layer Attributes #2, Tloušťka: 0 m; Object Layer Attributes #2, Faktor: 1; Object Layer Attributes #2, Označení: II.P5; Object Layer Attributes #2, Materiál: KERAMICKÁ DLAŽBA; Object Layer Attributes #2, Vztažná_výška: 0; Object Layer Attributes #2, Delta_výšky: 0; Object Layer Attributes #2, Podlaží: 1.NP; Object Layer Attributes #2, Číslo místnosti: K1.04a; Object Layer Attributes #2, Plošná únosnost: 3; Object Layer Attributes #2, Allright_Stavebni_dil_ID: 1469Ppl0000000592/02; Object Layer Attributes #2, Jednotka: m3; Object Layer Attributes #2, Název_objektu: Plocha podlahy; Object Layer Attributes #2, Kročejová neprůzvučnost: 54.5
 | K1.04a | CEILING | MALBA 0.005 m, SDK PODHLED 0.025 m | 1 | 0.005 | 0 | 1 | 1469Dpl0000000591/01 | m3 | Plocha stropu | NEW | 1.575 | 0.03 | 0 | NEMSOK - Object Layer Attributes #1, Kód prvku: MB03.03.1001; Object Layer Attributes #1, Práce: Malby a nátěry; Object Layer Attributes #1, Materiál: MALBA; Object Layer Attributes #1, Podlaží: 1.NP; Object Layer Attributes #1, Způsob provedení: ruční; Object Layer Attributes #2, Status: Nový; Object Layer Attributes #2, Kód prvku: PH01.03.0001; Object Layer Attributes #2, Práce: Suché stavební práce; Object Layer Attributes #2, Číslo_vrstvy: 2; Object Layer Attributes #2, Tloušťka_vrstvy: 0.025 m; Object Layer Attributes #2, Tloušťka: 0 m; Object Layer Attributes #2, Faktor: 1; Object Layer Attributes #2, Materiál: SDK PODHLED; Object Layer Attributes #2, Vztažná_výška: 0; Object Layer Attributes #2, Delta_výšky: 0; Object Layer Attributes #2, Allright_Stavebni_dil_ID: 1469Dpl0000000591/02; Object Layer Attributes #2, Jednotka: m3; Object Layer Attributes #2, Název_objektu: Plocha stropu; Object Layer Attributes #2, Požární odolnost: bez požadavku; Object Layer Attributes #2, Výška svěšení: 0.6 m; Object Layer Attributes #2, Únosnost bodová: 0.5 kg
 | K1.08 | FLOORING | layer 0.295 m, AKUSTICKÝ VINYL 0.005 m | 1 | 0.295 | 0 | 1 | 1469Ppl0000000626/01 | m3 | Plocha podlahy | NEW | 14.505 | 0.3 | 0 | NEMSOK - Object Layer Attributes #2, Status: Nový; Object Layer Attributes #2, Kód prvku: PD06.03.2001; Object Layer Attributes #2, Práce: Povlakové podlahy; Object Layer Attributes #2, Číslo_vrstvy: 2; Object Layer Attributes #2, Tloušťka_vrstvy: 0.005 m; Object Layer Attributes #2, Tloušťka: 0 m; Object Layer Attributes #2, Faktor: 1; Object Layer Attributes #2, Označení: II.P1; Object Layer Attributes #2, Materiál: AKUSTICKÝ VINYL; Object Layer Attributes #2, Vztažná_výška: 0; Object Layer Attributes #2, Delta_výšky: 0; Object Layer Attributes #2, Podlaží: 1.NP; Object Layer Attributes #2, Číslo místnosti: K1.08; Object Layer Attributes #2, Plošná únosnost: 5; Object Layer Attributes #2, Allright_Stavebni_dil_ID: 1469Ppl0000000626/02; Object Layer Attributes #2, Jednotka: m3; Object Layer Attributes #2, Název_objektu: Plocha podlahy
 | K1.08 | CEILING | MALBA 0.005 m, SDK PODHLED 0.025 m | 1 | 0.005 | 0 | 1 | 1469Dpl0000000625/01 | m3 | Plocha stropu | NEW | 14.505 | 0.03 | 0 | NEMSOK - Object Layer Attributes #1, Kód prvku: MB03.03.1001; Object Layer Attributes #1, Práce: Malby a nátěry; Object Layer Attributes #1, Materiál: MALBA; Object Layer Attributes #1, Podlaží: 1.NP; Object Layer Attributes #1, Způsob provedení: ruční; Object Layer Attributes #2, Status: Nový; Object Layer Attributes #2, Kód prvku: PH01.03.0001; Object Layer Attributes #2, Práce: Suché stavební práce; Object Layer Attributes #2, Číslo_vrstvy: 2; Object Layer Attributes #2, Tloušťka_vrstvy: 0.025 m; Object Layer Attributes #2, Tloušťka: 0 m; Object Layer Attributes #2, Faktor: 1; Object Layer Attributes #2, Materiál: SDK PODHLED; Object Layer Attributes #2, Vztažná_výška: 0; Object Layer Attributes #2, Delta_výšky: 0; Object Layer Attributes #2, Allright_Stavebni_dil_ID: 1469Dpl0000000625/02; Object Layer Attributes #2, Jednotka: m3; Object Layer Attributes #2, Název_objektu: Plocha stropu; Object Layer Attributes #2, Požární odolnost: bez požadavku; Object Layer Attributes #2, Výška svěšení: 0.6 m; Object Layer Attributes #2, Únosnost bodová: 0.5 kg
 | K1.08 | SKIRTINGBOARD | FABION |  |  |  |  |  |  |  | NEW | NEMSOK - Kód prvku: PD00.03.0000; Práce: Povlakové podlahy; Faktor: 1; Materiál: FABION; Vztažná_výška: 0; Delta_výšky: 0; Allright_Stavebni_dil_ID: 1469Liš0000002857; Jednotka: m; Název_objektu: Lišta
 | K1.07 | FLOORING | layer 0.295 m, AKUSTICKÝ VINYL 0.005 m | 1 | 0.295 | 0 | 1 | 1469Ppl0000000637/01 | m3 | Plocha podlahy | NEW | 42.221 | 0.3 | 0 | NEMSOK - Object Layer Attributes #2, Status: Nový; Object Layer Attributes #2, Kód prvku: PD06.03.2001; Object Layer Attributes #2, Práce: Povlakové podlahy; Object Layer Attributes #2, Číslo_vrstvy: 2; Object Layer Attributes #2, Tloušťka_vrstvy: 0.005 m; Object Layer Attributes #2, Tloušťka: 0 m; Object Layer Attributes #2, Faktor: 1; Object Layer Attributes #2, Označení: II.P1; Object Layer Attributes #2, Materiál: AKUSTICKÝ VINYL; Object Layer Attributes #2, Vztažná_výška: 0; Object Layer Attributes #2, Delta_výšky: 0; Object Layer Attributes #2, Podlaží: 1.NP; Object Layer Attributes #2, Číslo místnosti: K1.07; Object Layer Attributes #2, Plošná únosnost: 5; Object Layer Attributes #2, Allright_Stavebni_dil_ID: 1469Ppl0000000637/02; Object Layer Attributes #2, Jednotka: m3; Object Layer Attributes #2, Název_objektu: Plocha podlahy
 | K1.07 | CEILING | MALBA 0.005 m, SDK PODHLED 0.025 m | 1 | 0.005 | 0 | 1 | 1469Dpl0000000636/01 | m3 | Plocha stropu | NEW | 42.221 | 0.03 | 0 | NEMSOK - Object Layer Attributes #1, Kód prvku: MB03.03.1001; Object Layer Attributes #1, Práce: Malby a nátěry; Object Layer Attributes #1, Materiál: MALBA; Object Layer Attributes #1, Podlaží: 1.NP; Object Layer Attributes #1, Způsob provedení: ruční; Object Layer Attributes #2, Status: Nový; Object Layer Attributes #2, Kód prvku: PH01.03.0001; Object Layer Attributes #2, Práce: Suché stavební práce; Object Layer Attributes #2, Číslo_vrstvy: 2; Object Layer Attributes #2, Tloušťka_vrstvy: 0.025 m; Object Layer Attributes #2, Tloušťka: 0 m; Object Layer Attributes #2, Faktor: 1; Object Layer Attributes #2, Materiál: SDK PODHLED; Object Layer Attributes #2, Vztažná_výška: 0; Object Layer Attributes #2, Delta_výšky: 0; Object Layer Attributes #2, Allright_Stavebni_dil_ID: 1469Dpl0000000636/02; Object Layer Attributes #2, Jednotka: m3; Object Layer Attributes #2, Název_objektu: Plocha stropu; Object Layer Attributes #2, Požární odolnost: bez požadavku; Object Layer Attributes #2, Výška svěšení: 0.6 m; Object Layer Attributes #2, Únosnost bodová: 0.5 kg
 | K1.07 | SKIRTINGBOARD | FABION |  |  |  |  |  |  |  | NEW | NEMSOK - Kód prvku: PD00.03.0000; Práce: Povlakové podlahy; Faktor: 1; Materiál: FABION; Vztažná_výška: 0; Delta_výšky: 0; Allright_Stavebni_dil_ID: 1469Liš0000002858; Jednotka: m; Název_objektu: Lišta
 | K1.01 | FLOORING | layer 0.095 m, AKUSTICKÝ VINYL 0.005 m | 1 | 0.095 | 0 | 1 | 1469Ppl0000002694/01 | m3 | Plocha podlahy | NEW | 0.72 | 0.1 | 0 | NEMSOK - Object Layer Attributes #2, Status: Nový; Object Layer Attributes #2, Kód prvku: PD06.03.2001; Object Layer Attributes #2, Práce: Povlakové podlahy; Object Layer Attributes #2, Číslo_vrstvy: 2; Object Layer Attributes #2, Tloušťka_vrstvy: 0.005 m; Object Layer Attributes #2, Tloušťka: 0 m; Object Layer Attributes #2, Faktor: 1; Object Layer Attributes #2, Označení: II.P3; Object Layer Attributes #2, Materiál: AKUSTICKÝ VINYL; Object Layer Attributes #2, Vztažná_výška: 0; Object Layer Attributes #2, Delta_výšky: 0; Object Layer Attributes #2, Podlaží: 1.NP; Object Layer Attributes #2, Číslo místnosti: K1.01; Object Layer Attributes #2, Plošná únosnost: 3; Object Layer Attributes #2, Allright_Stavebni_dil_ID: 1469Ppl0000002694/02; Object Layer Attributes #2, Jednotka: m3; Object Layer Attributes #2, Název_objektu: Plocha podlahy; Object Layer Attributes #2, Kročejová neprůzvučnost: 54.5
 | K1.01 | CEILING | MALBA 0.005 m, SDK PODHLED 0.025 m | 1 | 0.005 | 0 | 1 | 1469Dpl0000002693/01 | m3 | Plocha stropu | NEW | 0.72 | 0.03 | 0 | NEMSOK - Object Layer Attributes #1, Kód prvku: MB03.03.1001; Object Layer Attributes #1, Práce: Malby a nátěry; Object Layer Attributes #1, Materiál: MALBA; Object Layer Attributes #1, Podlaží: 1.NP; Object Layer Attributes #1, Způsob provedení: ruční; Object Layer Attributes #2, Status: Nový; Object Layer Attributes #2, Kód prvku: PH01.03.0001; Object Layer Attributes #2, Práce: Suché stavební práce; Object Layer Attributes #2, Číslo_vrstvy: 2; Object Layer Attributes #2, Tloušťka_vrstvy: 0.025 m; Object Layer Attributes #2, Tloušťka: 0 m; Object Layer Attributes #2, Faktor: 1; Object Layer Attributes #2, Materiál: SDK PODHLED; Object Layer Attributes #2, Vztažná_výška: 0; Object Layer Attributes #2, Delta_výšky: 0; Object Layer Attributes #2, Allright_Stavebni_dil_ID: 1469Dpl0000002693/02; Object Layer Attributes #2, Jednotka: m3; Object Layer Attributes #2, Název_objektu: Plocha stropu; Object Layer Attributes #2, Požární odolnost: bez požadavku; Object Layer Attributes #2, Výška svěšení: 0.6 m; Object Layer Attributes #2, Únosnost bodová: 0.5 kg
 | 1.01 | FLOORING | layer 0.095 m, PŘÍRODNÍ LINOLEUM 0.005 m | 1 | 0.095 | 0 | 1 | 1469Ppl0000002745/01 | m3 | Plocha podlahy | NEW | 1.24 | 0.1 | 0 | NEMSOK - Object Layer Attributes #2, Status: Nový; Object Layer Attributes #2, Kód prvku: PD06.03.0001; Object Layer Attributes #2, Práce: Povlakové podlahy; Object Layer Attributes #2, Číslo_vrstvy: 2; Object Layer Attributes #2, Tloušťka_vrstvy: 0.005 m; Object Layer Attributes #2, Tloušťka: 0 m; Object Layer Attributes #2, Faktor: 1; Object Layer Attributes #2, Označení: II.P4; Object Layer Attributes #2, Materiál: PŘÍRODNÍ LINOLEUM; Object Layer Attributes #2, Vztažná_výška: 0; Object Layer Attributes #2, Delta_výšky: 0; Object Layer Attributes #2, Podlaží: 1.NP; Object Layer Attributes #2, Číslo místnosti: 1.01; Object Layer Attributes #2, Plošná únosnost: 3; Object Layer Attributes #2, Allright_Stavebni_dil_ID: 1469Ppl0000002745/02; Object Layer Attributes #2, Jednotka: m3; Object Layer Attributes #2, Název_objektu: Plocha podlahy; Object Layer Attributes #2, Kročejová neprůzvučnost: 58
 | 1.01 | CEILING | RASTR 1 0.03 m | 1 | 0.03 | 0 | 1 | 1469Dpl0000002744/01 | m3 | Plocha stropu | NEW | 1.24 | 0.03 | 0 | NEMSOK - Object Layer Attributes #1, Kód prvku: PH03.03.1001; Object Layer Attributes #1, Práce: Suché stavební práce; Object Layer Attributes #1, Materiál: RASTR 1; Object Layer Attributes #1, Výška svěšení: 0.6 m; Object Layer Attributes #1, Únosnost bodová: 0.5 kg; Pset_CoveringCommon - Flammability: bez požadavku
 | K1.14b | FLOORING | layer 0.285 m, KERAMICKÁ DLAŽBA 0.015 m | 1 | 0.285 | 0 | 1 | 1469Ppl0000003029/01 | m3 | Plocha podlahy | NEW | 1.63 | 0.3 | 0 | NEMSOK - Object Layer Attributes #2, Status: Nový; Object Layer Attributes #2, Kód prvku: PD01.03.0001; Object Layer Attributes #2, Práce: Obklady a dlažby; Object Layer Attributes #2, Číslo_vrstvy: 2; Object Layer Attributes #2, Tloušťka_vrstvy: 0.015 m; Object Layer Attributes #2, Tloušťka: 0 m; Object Layer Attributes #2, Faktor: 1; Object Layer Attributes #2, Označení: II.P2; Object Layer Attributes #2, Materiál: KERAMICKÁ DLAŽBA; Object Layer Attributes #2, Vztažná_výška: 0; Object Layer Attributes #2, Delta_výšky: 0; Object Layer Attributes #2, Podlaží: 1.NP; Object Layer Attributes #2, Číslo místnosti: K1.14b; Object Layer Attributes #2, Plošná únosnost: 5; Object Layer Attributes #2, Allright_Stavebni_dil_ID: 1469Ppl0000003029/02; Object Layer Attributes #2, Jednotka: m3; Object Layer Attributes #2, Název_objektu: Plocha podlahy
 | K1.14b | CEILING | RASTR 4 0.03 m | 1 | 0.03 | 0 | 1 | 1469Dpl0000003031/01 | m3 | Plocha stropu | NEW | 1.63 | 0.03 | 0 | NEMSOK - Object Layer Attributes #1, Kód prvku: PH03.03.4001; Object Layer Attributes #1, Práce: Suché stavební práce; Object Layer Attributes #1, Materiál: RASTR 4; Object Layer Attributes #1, Výška svěšení: 0.6 m; Object Layer Attributes #1, Únosnost bodová: 0.5 kg; Pset_CoveringCommon - Flammability: bez požadavku
 | 1.24 | CEILING | STÁVAJÍCÍ OMÍTKA 0.015 m, STÁVAJÍCÍ MALBA 0.005 m | 1 | 0.015 | 0 | 1 | 1469Dpl0000000172/01 | m3 | Plocha stropu | EXISTING | 22.116 | 0.02 | 0 | NEMSOK - Object Layer Attributes #1, Kód prvku: OM04.03.9001; Object Layer Attributes #1, Práce: Omítky a štuky; Object Layer Attributes #1, Materiál: STÁVAJÍCÍ OMÍTKA; Object Layer Attributes #2, Status: Stávající; Object Layer Attributes #2, Kód prvku: MB03.03.9001; Object Layer Attributes #2, Práce: Malby a nátěry; Object Layer Attributes #2, Číslo_vrstvy: 2; Object Layer Attributes #2, Tloušťka_vrstvy: 0.005 m; Object Layer Attributes #2, Tloušťka: 0 m; Object Layer Attributes #2, Faktor: 1; Object Layer Attributes #2, Materiál: STÁVAJÍCÍ MALBA; Object Layer Attributes #2, Vztažná_výška: 0; Object Layer Attributes #2, Delta_výšky: 0; Object Layer Attributes #2, Allright_Stavebni_dil_ID: 1469Dpl0000000172/02; Object Layer Attributes #2, Jednotka: m3; Object Layer Attributes #2, Název_objektu: Plocha stropu
 | 1.24 | FLOORING | STÁVAJÍCÍ LINO 0.005 m | 1 | 0.005 | 0 | 1 | 1469Ppl0000000171/01 | m3 | Plocha podlahy | EXISTING | 22.116 | 0.005 | 0 | NEMSOK - Object Layer Attributes #1, Kód prvku: PD06.03.9001; Object Layer Attributes #1, Práce: Povlakové podlahy; Object Layer Attributes #1, Materiál: STÁVAJÍCÍ LINO
 | 1.01a | FLOORING | layer 0.295 m, ČISTÍCÍ ZÓNA 0.005 m | 1 | 0.295 | 0 | 1 | 1469Ppl0000000896/01 | m3 | Plocha podlahy | NEW | 13.455 | 0.3 | 0 | NEMSOK - Object Layer Attributes #2, Status: Nový; Object Layer Attributes #2, Kód prvku: PD06.03.3001; Object Layer Attributes #2, Práce: Povlakové podlahy; Object Layer Attributes #2, Číslo_vrstvy: 2; Object Layer Attributes #2, Tloušťka_vrstvy: 0.005 m; Object Layer Attributes #2, Tloušťka: 0 m; Object Layer Attributes #2, Faktor: 1; Object Layer Attributes #2, Označení: I.P8; Object Layer Attributes #2, Materiál: ČISTÍCÍ ZÓNA; Object Layer Attributes #2, Vztažná_výška: 0; Object Layer Attributes #2, Delta_výšky: 0; Object Layer Attributes #2, Podlaží: 1.NP; Object Layer Attributes #2, Číslo místnosti: 1.01a; Object Layer Attributes #2, Plošná únosnost: 5; Object Layer Attributes #2, Allright_Stavebni_dil_ID: 1469Ppl0000000896/02; Object Layer Attributes #2, Jednotka: m3; Object Layer Attributes #2, Název_objektu: Plocha podlahy
 | 1.01a | CEILING | MALBA 0.005 m, SDK PODHLED 0.025 m | 1 | 0.005 | 0 | 1 | 1469Dpl0000000895/01 | m3 | Plocha stropu | NEW | 13.455 | 0.03 | 0 | NEMSOK - Object Layer Attributes #1, Kód prvku: MB03.03.1001; Object Layer Attributes #1, Práce: Malby a nátěry; Object Layer Attributes #1, Materiál: MALBA; Object Layer Attributes #1, Podlaží: 1.NP; Object Layer Attributes #1, Způsob provedení: ruční; Object Layer Attributes #2, Status: Nový; Object Layer Attributes #2, Kód prvku: PH01.03.1001; Object Layer Attributes #2, Práce: Suché stavební práce; Object Layer Attributes #2, Číslo_vrstvy: 2; Object Layer Attributes #2, Tloušťka_vrstvy: 0.025 m; Object Layer Attributes #2, Tloušťka: 0 m; Object Layer Attributes #2, Faktor: 1; Object Layer Attributes #2, Materiál: SDK PODHLED; Object Layer Attributes #2, Vztažná_výška: 0; Object Layer Attributes #2, Delta_výšky: 0; Object Layer Attributes #2, Allright_Stavebni_dil_ID: 1469Dpl0000000895/02; Object Layer Attributes #2, Jednotka: m3; Object Layer Attributes #2, Název_objektu: Plocha stropu; Object Layer Attributes #2, Požární odolnost: bez požadavku; Object Layer Attributes #2, Výška svěšení: 0.6 m; Object Layer Attributes #2, Únosnost bodová: 0.5 kg
 | 1.01b | FLOORING | layer 0.295 m, PŘÍRODNÍ LINOLEUM 0.005 m | 1 | 0.295 | 0 | 1 | 1469Ppl0000000909/01 | m3 | Plocha podlahy | NEW | 76.088 | 0.3 | 0 | NEMSOK - Object Layer Attributes #2, Status: Nový; Object Layer Attributes #2, Kód prvku: PD06.03.0001; Object Layer Attributes #2, Práce: Povlakové podlahy; Object Layer Attributes #2, Číslo_vrstvy: 2; Object Layer Attributes #2, Tloušťka_vrstvy: 0.005 m; Object Layer Attributes #2, Tloušťka: 0 m; Object Layer Attributes #2, Faktor: 1; Object Layer Attributes #2, Označení: I.P5; Object Layer Attributes #2, Materiál: PŘÍRODNÍ LINOLEUM; Object Layer Attributes #2, Vztažná_výška: 0; Object Layer Attributes #2, Delta_výšky: 0; Object Layer Attributes #2, Podlaží: 1.NP; Object Layer Attributes #2, Číslo místnosti: 1.01b; Object Layer Attributes #2, Plošná únosnost: 5; Object Layer Attributes #2, Allright_Stavebni_dil_ID: 1469Ppl0000000909/02; Object Layer Attributes #2, Jednotka: m3; Object Layer Attributes #2, Název_objektu: Plocha podlahy
 | 1.01b | SKIRTINGBOARD | FABION |  |  |  |  |  |  |  | NEW | NEMSOK - Kód prvku: PD00.03.0000; Práce: Povlakové podlahy; Faktor: 1; Materiál: FABION; Vztažná_výška: 0; Delta_výšky: 0; Allright_Stavebni_dil_ID: 1469Liš0000002864; Jednotka: m; Název_objektu: Lišta
 | 1.01b | CEILING | RASTR 1/SDK PODHLED 0.03 m | 1 | 0.03 | 0 | 1 | 1469Dpl0000000908/01 | m3 | Plocha stropu | NEW | 76.088 | 0.03 | 0 | NEMSOK - Object Layer Attributes #1, Kód prvku: PH03.03.1001; Object Layer Attributes #1, Práce: Suché stavební práce; Object Layer Attributes #1, Materiál: RASTR 1/SDK PODHLED; Object Layer Attributes #1, Výška svěšení: 0.6 m; Object Layer Attributes #1, Únosnost bodová: 0.5 kg; Pset_CoveringCommon - Flammability: bez požadavku
 | 1.02 | FLOORING | layer 0.295 m, ELEKTROSTATICKÝ VINYL 0.005 m | 1 | 0.295 | 0 | 1 | 1469Ppl0000000918/01 | m3 | Plocha podlahy | NEW | 21.736 | 0.3 | 0 | NEMSOK - Object Layer Attributes #2, Status: Nový; Object Layer Attributes #2, Kód prvku: PD06.03.1001; Object Layer Attributes #2, Práce: Povlakové podlahy; Object Layer Attributes #2, Číslo_vrstvy: 2; Object Layer Attributes #2, Tloušťka_vrstvy: 0.005 m; Object Layer Attributes #2, Tloušťka: 0 m; Object Layer Attributes #2, Faktor: 1; Object Layer Attributes #2, Označení: I.P7; Object Layer Attributes #2, Materiál: ELEKTROSTATICKÝ VINYL; Object Layer Attributes #2, Vztažná_výška: 0; Object Layer Attributes #2, Delta_výšky: 0; Object Layer Attributes #2, Podlaží: 1.NP; Object Layer Attributes #2, Číslo místnosti: 1.02; Object Layer Attributes #2, Plošná únosnost: 5; Object Layer Attributes #2, Allright_Stavebni_dil_ID: 1469Ppl0000000918/02; Object Layer Attributes #2, Jednotka: m3; Object Layer Attributes #2, Název_objektu: Plocha podlahy
 | 1.02 | SKIRTINGBOARD | FABION |  |  |  |  |  |  |  | NEW | NEMSOK - Kód prvku: PD00.03.0000; Práce: Povlakové podlahy; Faktor: 1; Materiál: FABION; Vztažná_výška: 0; Delta_výšky: 0; Allright_Stavebni_dil_ID: 1469Liš0000002866; Jednotka: m; Název_objektu: Lišta
 | 1.02 | CEILING | RASTR 3 0.03 m | 1 | 0.03 | 0 | 1 | 1469Dpl0000000917/01 | m3 | Plocha stropu | NEW | 21.736 | 0.03 | 0 | NEMSOK - Object Layer Attributes #1, Kód prvku: PH03.03.3001; Object Layer Attributes #1, Práce: Suché stavební práce; Object Layer Attributes #1, Materiál: RASTR 3; Object Layer Attributes #1, Výška svěšení: 0.6 m; Object Layer Attributes #1, Únosnost bodová: 0.5 kg; Pset_CoveringCommon - Flammability: bez požadavku
I.P9 | 1.03 | FLOORING | layer 0.295 m, ELEKTROSTATICKÝ VINYL 0.005 m | 1 | 0.295 | 0 | 1 | 1469Ppl0000000927/01 | m3 | Plocha podlahy | NEW | 26.681 | 0.3 | 0 | NEMSOK - Object Layer Attributes #2, Status: Nový; Object Layer Attributes #2, Kód prvku: PD06.03.1001; Object Layer Attributes #2, Práce: Povlakové podlahy; Object Layer Attributes #2, Číslo_vrstvy: 2; Object Layer Attributes #2, Tloušťka_vrstvy: 0.005 m; Object Layer Attributes #2, Tloušťka: 0 m; Object Layer Attributes #2, Faktor: 1; Object Layer Attributes #2, Označení: I.P7, I.P9; Object Layer Attributes #2, Materiál: ELEKTROSTATICKÝ VINYL; Object Layer Attributes #2, Vztažná_výška: 0; Object Layer Attributes #2, Delta_výšky: 0; Object Layer Attributes #2, Podlaží: 1.NP; Object Layer Attributes #2, Číslo místnosti: 1.03; Object Layer Attributes #2, Plošná únosnost: 3; Object Layer Attributes #2, Allright_Stavebni_dil_ID: 1469Ppl0000000927/02; Object Layer Attributes #2, Jednotka: m3; Object Layer Attributes #2, Název_objektu: Plocha podlahy; Object Layer Attributes #1, Označení: I.P9; Object Layer Attributes #2, Kročejová neprůzvučnost: 54.5
 | 1.03 | SKIRTINGBOARD | FABION |  |  |  |  |  |  |  | NEW | NEMSOK - Kód prvku: PD00.03.0000; Práce: Povlakové podlahy; Faktor: 1; Materiál: FABION; Vztažná_výška: 0; Delta_výšky: 0; Allright_Stavebni_dil_ID: 1469Liš0000002869; Jednotka: m; Název_objektu: Lišta
 | 1.03 | CEILING | RASTR 1 0.03 m | 1 | 0.03 | 0 | 1 | 1469Dpl0000000926/01 | m3 | Plocha stropu | NEW | 26.681 | 0.03 | 0 | NEMSOK - Object Layer Attributes #1, Kód prvku: PH03.03.1001; Object Layer Attributes #1, Práce: Suché stavební práce; Object Layer Attributes #1, Materiál: RASTR 1; Object Layer Attributes #1, Výška svěšení: 0.6 m; Object Layer Attributes #1, Únosnost bodová: 0.5 kg; Pset_CoveringCommon - Flammability: bez požadavku
I.P9 | 1.08 | FLOORING | layer 0.145 m, ELEKTROSTATICKÝ VINYL 0.005 m | 1 | 0.145 | 0 | 1 | 1469Ppl0000000936/01 | m3 | Plocha podlahy | NEW | 50.913 | 0.15 | 0 | NEMSOK - Object Layer Attributes #2, Status: Nový; Object Layer Attributes #2, Kód prvku: PD06.03.1001; Object Layer Attributes #2, Práce: Povlakové podlahy; Object Layer Attributes #2, Číslo_vrstvy: 2; Object Layer Attributes #2, Tloušťka_vrstvy: 0.005 m; Object Layer Attributes #2, Tloušťka: 0 m; Object Layer Attributes #2, Faktor: 1; Object Layer Attributes #2, Označení: I.P7, I.P9; Object Layer Attributes #2, Materiál: ELEKTROSTATICKÝ VINYL; Object Layer Attributes #2, Vztažná_výška: 0; Object Layer Attributes #2, Delta_výšky: 0; Object Layer Attributes #2, Podlaží: 1.NP; Object Layer Attributes #2, Číslo místnosti: 1.08; Object Layer Attributes #2, Plošná únosnost: 3; Object Layer Attributes #2, Allright_Stavebni_dil_ID: 1469Ppl0000000936/02; Object Layer Attributes #2, Jednotka: m3; Object Layer Attributes #2, Název_objektu: Plocha podlahy; Object Layer Attributes #1, Označení: I.P9; Object Layer Attributes #2, Kročejová neprůzvučnost: 54.5
 | 1.08 | SKIRTINGBOARD | FABION |  |  |  |  |  |  |  | NEW | NEMSOK - Kód prvku: PD00.03.0000; Práce: Povlakové podlahy; Faktor: 1; Materiál: FABION; Vztažná_výška: 0; Delta_výšky: 0; Allright_Stavebni_dil_ID: 1469Liš0000002873; Jednotka: m; Název_objektu: Lišta
 | 1.08 | CEILING | RASTR 3 0.03 m | 1 | 0.03 | 0 | 1 | 1469Dpl0000000935/01 | m3 | Plocha stropu | NEW | 50.913 | 0.03 | 0 | NEMSOK - Object Layer Attributes #1, Kód prvku: PH03.03.3001; Object Layer Attributes #1, Práce: Suché stavební práce; Object Layer Attributes #1, Materiál: RASTR 3; Object Layer Attributes #1, Výška svěšení: 0.6 m; Object Layer Attributes #1, Únosnost bodová: 0.5 kg; Pset_CoveringCommon - Flammability: bez požadavku
 | 1.09 | FLOORING | layer 0.295 m, ELEKTROSTATICKÝ VINYL 0.005 m | 1 | 0.295 | 0 | 1 | 1469Ppl0000000996/01 | m3 | Plocha podlahy | NEW | 26.989 | 0.3 | 0 | NEMSOK - Object Layer Attributes #2, Status: Nový; Object Layer Attributes #2, Kód prvku: PD06.03.1001; Object Layer Attributes #2, Práce: Povlakové podlahy; Object Layer Attributes #2, Číslo_vrstvy: 2; Object Layer Attributes #2, Tloušťka_vrstvy: 0.005 m; Object Layer Attributes #2, Tloušťka: 0 m; Object Layer Attributes #2, Faktor: 1; Object Layer Attributes #2, Označení: I.P7; Object Layer Attributes #2, Materiál: ELEKTROSTATICKÝ VINYL; Object Layer Attributes #2, Vztažná_výška: 0; Object Layer Attributes #2, Delta_výšky: 0; Object Layer Attributes #2, Podlaží: 1.NP; Object Layer Attributes #2, Číslo místnosti: 1.09; Object Layer Attributes #2, Plošná únosnost: 5; Object Layer Attributes #2, Allright_Stavebni_dil_ID: 1469Ppl0000000996/02; Object Layer Attributes #2, Jednotka: m3; Object Layer Attributes #2, Název_objektu: Plocha podlahy
 | 1.09 | SKIRTINGBOARD | FABION |  |  |  |  |  |  |  | NEW | NEMSOK - Kód prvku: PD00.03.0000; Práce: Povlakové podlahy; Faktor: 1; Materiál: FABION; Vztažná_výška: 0; Delta_výšky: 0; Allright_Stavebni_dil_ID: 1469Liš0000002875; Jednotka: m; Název_objektu: Lišta
 | 1.09 | CEILING | RASTR 3 0.03 m | 1 | 0.03 | 0 | 1 | 1469Dpl0000000995/01 | m3 | Plocha stropu | NEW | 26.989 | 0.03 | 0 | NEMSOK - Object Layer Attributes #1, Kód prvku: PH03.03.3001; Object Layer Attributes #1, Práce: Suché stavební práce; Object Layer Attributes #1, Materiál: RASTR 3; Object Layer Attributes #1, Výška svěšení: 0.6 m; Object Layer Attributes #1, Únosnost bodová: 0.5 kg; Pset_CoveringCommon - Flammability: bez požadavku
 | 1.10 | FLOORING | layer 0.145 m, ELEKTROSTATICKÝ VINYL 0.005 m | 1 | 0.145 | 0 | 1 | 1469Ppl0000001028/01 | m3 | Plocha podlahy | NEW | 24.903 | 0.15 | 0 | NEMSOK - Object Layer Attributes #2, Status: Nový; Object Layer Attributes #2, Kód prvku: PD06.03.1001; Object Layer Attributes #2, Práce: Povlakové podlahy; Object Layer Attributes #2, Číslo_vrstvy: 2; Object Layer Attributes #2, Tloušťka_vrstvy: 0.005 m; Object Layer Attributes #2, Tloušťka: 0 m; Object Layer Attributes #2, Faktor: 1; Object Layer Attributes #2, Označení: I.P9; Object Layer Attributes #2, Materiál: ELEKTROSTATICKÝ VINYL; Object Layer Attributes #2, Vztažná_výška: 0; Object Layer Attributes #2, Delta_výšky: 0; Object Layer Attributes #2, Podlaží: 1.NP; Object Layer Attributes #2, Číslo místnosti: 1.10; Object Layer Attributes #2, Plošná únosnost: 3; Object Layer Attributes #2, Allright_Stavebni_dil_ID: 1469Ppl0000001028/02; Object Layer Attributes #2, Jednotka: m3; Object Layer Attributes #2, Název_objektu: Plocha podlahy; Object Layer Attributes #2, Kročejová neprůzvučnost: 54.5
 | 1.10 | SKIRTINGBOARD | FABION |  |  |  |  |  |  |  | NEW | NEMSOK - Kód prvku: PD00.03.0000; Práce: Povlakové podlahy; Faktor: 1; Materiál: FABION; Vztažná_výška: 0; Delta_výšky: 0; Allright_Stavebni_dil_ID: 1469Liš0000002876; Jednotka: m; Název_objektu: Lišta
 | 1.10 | CEILING | RASTR 3 0.03 m | 1 | 0.03 | 0 | 1 | 1469Dpl0000001027/01 | m3 | Plocha stropu | NEW | 24.903 | 0.03 | 0 | NEMSOK - Object Layer Attributes #1, Kód prvku: PH03.03.3001; Object Layer Attributes #1, Práce: Suché stavební práce; Object Layer Attributes #1, Materiál: RASTR 3; Object Layer Attributes #1, Výška svěšení: 0.6 m; Object Layer Attributes #1, Únosnost bodová: 0.5 kg; Pset_CoveringCommon - Flammability: bez požadavku
 | 1.11 | FLOORING | layer 0.145 m, ELEKTROSTATICKÝ VINYL 0.005 m | 1 | 0.145 | 0 | 1 | 1469Ppl0000001037/01 | m3 | Plocha podlahy | NEW | 12.41 | 0.15 | 0 | NEMSOK - Object Layer Attributes #2, Status: Nový; Object Layer Attributes #2, Kód prvku: PD06.03.1001; Object Layer Attributes #2, Práce: Povlakové podlahy; Object Layer Attributes #2, Číslo_vrstvy: 2; Object Layer Attributes #2, Tloušťka_vrstvy: 0.005 m; Object Layer Attributes #2, Tloušťka: 0 m; Object Layer Attributes #2, Faktor: 1; Object Layer Attributes #2, Označení: I.P9; Object Layer Attributes #2, Materiál: ELEKTROSTATICKÝ VINYL; Object Layer Attributes #2, Vztažná_výška: 0; Object Layer Attributes #2, Delta_výšky: 0; Object Layer Attributes #2, Podlaží: 1.NP; Object Layer Attributes #2, Číslo místnosti: 1.11; Object Layer Attributes #2, Plošná únosnost: 3; Object Layer Attributes #2, Allright_Stavebni_dil_ID: 1469Ppl0000001037/02; Object Layer Attributes #2, Jednotka: m3; Object Layer Attributes #2, Název_objektu: Plocha podlahy; Object Layer Attributes #2, Kročejová neprůzvučnost: 54.5
 | 1.11 | SKIRTINGBOARD | FABION |  |  |  |  |  |  |  | NEW | NEMSOK - Kód prvku: PD00.03.0000; Práce: Povlakové podlahy; Faktor: 1; Materiál: FABION; Vztažná_výška: 0; Delta_výšky: 0; Allright_Stavebni_dil_ID: 1469Liš0000002877; Jednotka: m; Název_objektu: Lišta
 | 1.11 | CEILING | RASTR 3 0.03 m | 1 | 0.03 | 0 | 1 | 1469Dpl0000001036/01 | m3 | Plocha stropu | NEW | 12.41 | 0.03 | 0 | NEMSOK - Object Layer Attributes #1, Kód prvku: PH03.03.3001; Object Layer Attributes #1, Práce: Suché stavební práce; Object Layer Attributes #1, Materiál: RASTR 3; Object Layer Attributes #1, Výška svěšení: 0.6 m; Object Layer Attributes #1, Únosnost bodová: 0.5 kg; Pset_CoveringCommon - Flammability: bez požadavku
 | 1.12 | FLOORING | layer 0.145 m, ELEKTROSTATICKÝ VINYL 0.005 m | 1 | 0.145 | 0 | 1 | 1469Ppl0000001066/01 | m3 | Plocha podlahy | NEW | 12.41 | 0.15 | 0 | NEMSOK - Object Layer Attributes #2, Status: Nový; Object Layer Attributes #2, Kód prvku: PD06.03.1001; Object Layer Attributes #2, Práce: Povlakové podlahy; Object Layer Attributes #2, Číslo_vrstvy: 2; Object Layer Attributes #2, Tloušťka_vrstvy: 0.005 m; Object Layer Attributes #2, Tloušťka: 0 m; Object Layer Attributes #2, Faktor: 1; Object Layer Attributes #2, Označení: I.P9; Object Layer Attributes #2, Materiál: ELEKTROSTATICKÝ VINYL; Object Layer Attributes #2, Vztažná_výška: 0; Object Layer Attributes #2, Delta_výšky: 0; Object Layer Attributes #2, Podlaží: 1.NP; Object Layer Attributes #2, Číslo místnosti: 1.12; Object Layer Attributes #2, Plošná únosnost: 3; Object Layer Attributes #2, Allright_Stavebni_dil_ID: 1469Ppl0000001066/02; Object Layer Attributes #2, Jednotka: m3; Object Layer Attributes #2, Název_objektu: Plocha podlahy; Object Layer Attributes #2, Kročejová neprůzvučnost: 54.5
 | 1.12 | SKIRTINGBOARD | FABION |  |  |  |  |  |  |  | NEW | NEMSOK - Kód prvku: PD00.03.0000; Práce: Povlakové podlahy; Faktor: 1; Materiál: FABION; Vztažná_výška: 0; Delta_výšky: 0; Allright_Stavebni_dil_ID: 1469Liš0000002878; Jednotka: m; Název_objektu: Lišta
 | 1.12 | CEILING | RASTR 3 0.03 m | 1 | 0.03 | 0 | 1 | 1469Dpl0000001065/01 | m3 | Plocha stropu | NEW | 12.41 | 0.03 | 0 | NEMSOK - Object Layer Attributes #1, Kód prvku: PH03.03.3001; Object Layer Attributes #1, Práce: Suché stavební práce; Object Layer Attributes #1, Materiál: RASTR 3; Object Layer Attributes #1, Výška svěšení: 0.6 m; Object Layer Attributes #1, Únosnost bodová: 0.5 kg; Pset_CoveringCommon - Flammability: bez požadavku
I.P7 | 1.13 | FLOORING | layer 0.295 m, ELEKTROSTATICKÝ VINYL 0.005 m | 1 | 0.295 | 0 | 1 | 1469Ppl0000001075/01 | m3 | Plocha podlahy | NEW | 10.585 | 0.3 | 0 | NEMSOK - Object Layer Attributes #2, Status: Nový; Object Layer Attributes #2, Kód prvku: PD06.03.1001; Object Layer Attributes #2, Práce: Povlakové podlahy; Object Layer Attributes #2, Číslo_vrstvy: 2; Object Layer Attributes #2, Tloušťka_vrstvy: 0.005 m; Object Layer Attributes #2, Tloušťka: 0 m; Object Layer Attributes #2, Faktor: 1; Object Layer Attributes #2, Označení: I.P7, I.P9; Object Layer Attributes #2, Materiál: ELEKTROSTATICKÝ VINYL; Object Layer Attributes #2, Vztažná_výška: 0; Object Layer Attributes #2, Delta_výšky: 0; Object Layer Attributes #2, Podlaží: 1.NP; Object Layer Attributes #2, Číslo místnosti: 1.13; Object Layer Attributes #2, Plošná únosnost: 5; Object Layer Attributes #2, Allright_Stavebni_dil_ID: 1469Ppl0000001075/02; Object Layer Attributes #2, Jednotka: m3; Object Layer Attributes #2, Název_objektu: Plocha podlahy; Object Layer Attributes #1, Označení: I.P7
 | 1.13 | SKIRTINGBOARD | FABION |  |  |  |  |  |  |  | NEW | NEMSOK - Kód prvku: PD00.03.0000; Práce: Povlakové podlahy; Faktor: 1; Materiál: FABION; Vztažná_výška: 0; Delta_výšky: 0; Allright_Stavebni_dil_ID: 1469Liš0000002880; Jednotka: m; Název_objektu: Lišta
 | 1.13 | CEILING | RASTR 3 0.03 m | 1 | 0.03 | 0 | 1 | 1469Dpl0000001074/01 | m3 | Plocha stropu | NEW | 10.585 | 0.03 | 0 | NEMSOK - Object Layer Attributes #1, Kód prvku: PH03.03.3001; Object Layer Attributes #1, Práce: Suché stavební práce; Object Layer Attributes #1, Materiál: RASTR 3; Object Layer Attributes #1, Výška svěšení: 0.6 m; Object Layer Attributes #1, Únosnost bodová: 0.5 kg; Pset_CoveringCommon - Flammability: bez požadavku
 | 1.14 | FLOORING | layer 0.295 m, ELEKTROSTATICKÝ VINYL 0.005 m | 1 | 0.295 | 0 | 1 | 1469Ppl0000001084/01 | m3 | Plocha podlahy | NEW | 12.41 | 0.3 | 0 | NEMSOK - Object Layer Attributes #2, Status: Nový; Object Layer Attributes #2, Kód prvku: PD06.03.1001; Object Layer Attributes #2, Práce: Povlakové podlahy; Object Layer Attributes #2, Číslo_vrstvy: 2; Object Layer Attributes #2, Tloušťka_vrstvy: 0.005 m; Object Layer Attributes #2, Tloušťka: 0 m; Object Layer Attributes #2, Faktor: 1; Object Layer Attributes #2, Označení: I.P7; Object Layer Attributes #2, Materiál: ELEKTROSTATICKÝ VINYL; Object Layer Attributes #2, Vztažná_výška: 0; Object Layer Attributes #2, Delta_výšky: 0; Object Layer Attributes #2, Podlaží: 1.NP; Object Layer Attributes #2, Číslo místnosti: 1.14; Object Layer Attributes #2, Plošná únosnost: 5; Object Layer Attributes #2, Allright_Stavebni_dil_ID: 1469Ppl0000001084/02; Object Layer Attributes #2, Jednotka: m3; Object Layer Attributes #2, Název_objektu: Plocha podlahy
 | 1.14 | SKIRTINGBOARD | FABION |  |  |  |  |  |  |  | NEW | NEMSOK - Kód prvku: PD00.03.0000; Práce: Povlakové podlahy; Faktor: 1; Materiál: FABION; Vztažná_výška: 0; Delta_výšky: 0; Allright_Stavebni_dil_ID: 1469Liš0000002881; Jednotka: m; Název_objektu: Lišta
 | 1.14 | CEILING | RASTR 3 0.03 m | 1 | 0.03 | 0 | 1 | 1469Dpl0000001083/01 | m3 | Plocha stropu | NEW | 12.41 | 0.03 | 0 | NEMSOK - Object Layer Attributes #1, Kód prvku: PH03.03.3001; Object Layer Attributes #1, Práce: Suché stavební práce; Object Layer Attributes #1, Materiál: RASTR 3; Object Layer Attributes #1, Výška svěšení: 0.6 m; Object Layer Attributes #1, Únosnost bodová: 0.5 kg; Pset_CoveringCommon - Flammability: bez požadavku
 | 1.15 | FLOORING | layer 0.295 m, ELEKTROSTATICKÝ VINYL 0.005 m | 1 | 0.295 | 0 | 1 | 1469Ppl0000001093/01 | m3 | Plocha podlahy | NEW | 11.744 | 0.3 | 0 | NEMSOK - Object Layer Attributes #2, Status: Nový; Object Layer Attributes #2, Kód prvku: PD06.03.1001; Object Layer Attributes #2, Práce: Povlakové podlahy; Object Layer Attributes #2, Číslo_vrstvy: 2; Object Layer Attributes #2, Tloušťka_vrstvy: 0.005 m; Object Layer Attributes #2, Tloušťka: 0 m; Object Layer Attributes #2, Faktor: 1; Object Layer Attributes #2, Označení: I.P7; Object Layer Attributes #2, Materiál: ELEKTROSTATICKÝ VINYL; Object Layer Attributes #2, Vztažná_výška: 0; Object Layer Attributes #2, Delta_výšky: 0; Object Layer Attributes #2, Podlaží: 1.NP; Object Layer Attributes #2, Číslo místnosti: 1.15; Object Layer Attributes #2, Plošná únosnost: 5; Object Layer Attributes #2, Allright_Stavebni_dil_ID: 1469Ppl0000001093/02; Object Layer Attributes #2, Jednotka: m3; Object Layer Attributes #2, Název_objektu: Plocha podlahy
 | 1.15 | SKIRTINGBOARD | FABION |  |  |  |  |  |  |  | NEW | NEMSOK - Kód prvku: PD00.03.0000; Práce: Povlakové podlahy; Faktor: 1; Materiál: FABION; Vztažná_výška: 0; Delta_výšky: 0; Allright_Stavebni_dil_ID: 1469Liš0000002882; Jednotka: m; Název_objektu: Lišta
 | 1.15 | CEILING | RASTR 3 0.03 m | 1 | 0.03 | 0 | 1 | 1469Dpl0000001092/01 | m3 | Plocha stropu | NEW | 11.744 | 0.03 | 0 | NEMSOK - Object Layer Attributes #1, Kód prvku: PH03.03.3001; Object Layer Attributes #1, Práce: Suché stavební práce; Object Layer Attributes #1, Materiál: RASTR 3; Object Layer Attributes #1, Výška svěšení: 0.6 m; Object Layer Attributes #1, Únosnost bodová: 0.5 kg; Pset_CoveringCommon - Flammability: bez požadavku
 | 1.16 | FLOORING | layer 0.295 m, ELEKTROSTATICKÝ VINYL 0.005 m | 1 | 0.295 | 0 | 1 | 1469Ppl0000001102/01 | m3 | Plocha podlahy | NEW | 23.561 | 0.3 | 0 | NEMSOK - Object Layer Attributes #2, Status: Nový; Object Layer Attributes #2, Kód prvku: PD06.03.1001; Object Layer Attributes #2, Práce: Povlakové podlahy; Object Layer Attributes #2, Číslo_vrstvy: 2; Object Layer Attributes #2, Tloušťka_vrstvy: 0.005 m; Object Layer Attributes #2, Tloušťka: 0 m; Object Layer Attributes #2, Faktor: 1; Object Layer Attributes #2, Označení: I.P7; Object Layer Attributes #2, Materiál: ELEKTROSTATICKÝ VINYL; Object Layer Attributes #2, Vztažná_výška: 0; Object Layer Attributes #2, Delta_výšky: 0; Object Layer Attributes #2, Podlaží: 1.NP; Object Layer Attributes #2, Číslo místnosti: 1.16; Object Layer Attributes #2, Plošná únosnost: 5; Object Layer Attributes #2, Allright_Stavebni_dil_ID: 1469Ppl0000001102/02; Object Layer Attributes #2, Jednotka: m3; Object Layer Attributes #2, Název_objektu: Plocha podlahy
 | 1.16 | SKIRTINGBOARD | FABION |  |  |  |  |  |  |  | NEW | NEMSOK - Kód prvku: PD00.03.0000; Práce: Povlakové podlahy; Faktor: 1; Materiál: FABION; Vztažná_výška: 0; Delta_výšky: 0; Allright_Stavebni_dil_ID: 1469Liš0000002883; Jednotka: m; Název_objektu: Lišta
 | 1.16 | CEILING | RASTR 3 0.03 m | 1 | 0.03 | 0 | 1 | 1469Dpl0000001101/01 | m3 | Plocha stropu | NEW | 23.561 | 0.03 | 0 | NEMSOK - Object Layer Attributes #1, Kód prvku: PH03.03.3001; Object Layer Attributes #1, Práce: Suché stavební práce; Object Layer Attributes #1, Materiál: RASTR 3; Object Layer Attributes #1, Výška svěšení: 0.6 m; Object Layer Attributes #1, Únosnost bodová: 0.5 kg; Pset_CoveringCommon - Flammability: bez požadavku
 | 1.17 | FLOORING | layer 0.295 m, PŘÍRODNÍ LINOLEUM 0.005 m | 1 | 0.295 | 0 | 1 | 1469Ppl0000001125/01 | m3 | Plocha podlahy | NEW | 12.015 | 0.3 | 0 | NEMSOK - Object Layer Attributes #2, Status: Nový; Object Layer Attributes #2, Kód prvku: PD06.03.0001; Object Layer Attributes #2, Práce: Povlakové podlahy; Object Layer Attributes #2, Číslo_vrstvy: 2; Object Layer Attributes #2, Tloušťka_vrstvy: 0.005 m; Object Layer Attributes #2, Tloušťka: 0 m; Object Layer Attributes #2, Faktor: 1; Object Layer Attributes #2, Označení: I.P5; Object Layer Attributes #2, Materiál: PŘÍRODNÍ LINOLEUM; Object Layer Attributes #2, Vztažná_výška: 0; Object Layer Attributes #2, Delta_výšky: 0; Object Layer Attributes #2, Podlaží: 1.NP; Object Layer Attributes #2, Číslo místnosti: 1.17; Object Layer Attributes #2, Plošná únosnost: 5; Object Layer Attributes #2, Allright_Stavebni_dil_ID: 1469Ppl0000001125/02; Object Layer Attributes #2, Jednotka: m3; Object Layer Attributes #2, Název_objektu: Plocha podlahy
 | 1.17 | SKIRTINGBOARD | SOKLOVÁ PVC LIŠTA |  |  |  |  |  |  |  | NEW | NEMSOK - Kód prvku: PD00.03.0000; Práce: Povlakové podlahy; Faktor: 1; Materiál: SOKLOVÁ PVC LIŠTA; Vztažná_výška: 0; Delta_výšky: 0; Allright_Stavebni_dil_ID: 1469Liš0000002884; Jednotka: m; Název_objektu: Lišta
 | 1.17 | CEILING | RASTR 2 0.03 m | 1 | 0.03 | 0 | 1 | 1469Dpl0000001124/01 | m3 | Plocha stropu | NEW | 12.015 | 0.03 | 0 | NEMSOK - Object Layer Attributes #1, Kód prvku: PH03.03.2001; Object Layer Attributes #1, Práce: Suché stavební práce; Object Layer Attributes #1, Materiál: RASTR 2; Object Layer Attributes #1, Výška svěšení: 0.6 m; Object Layer Attributes #1, Únosnost bodová: 0.5 kg; Pset_CoveringCommon - Flammability: bez požadavku
 | 1.18 | FLOORING | layer 0.295 m, PŘÍRODNÍ LINOLEUM 0.005 m | 1 | 0.295 | 0 | 1 | 1469Ppl0000001134/01 | m3 | Plocha podlahy | NEW | 13.239 | 0.3 | 0 | NEMSOK - Object Layer Attributes #2, Status: Nový; Object Layer Attributes #2, Kód prvku: PD06.03.0001; Object Layer Attributes #2, Práce: Povlakové podlahy; Object Layer Attributes #2, Číslo_vrstvy: 2; Object Layer Attributes #2, Tloušťka_vrstvy: 0.005 m; Object Layer Attributes #2, Tloušťka: 0 m; Object Layer Attributes #2, Faktor: 1; Object Layer Attributes #2, Označení: I.P5; Object Layer Attributes #2, Materiál: PŘÍRODNÍ LINOLEUM; Object Layer Attributes #2, Vztažná_výška: 0; Object Layer Attributes #2, Delta_výšky: 0; Object Layer Attributes #2, Podlaží: 1.NP; Object Layer Attributes #2, Číslo místnosti: 1.18; Object Layer Attributes #2, Plošná únosnost: 5; Object Layer Attributes #2, Allright_Stavebni_dil_ID: 1469Ppl0000001134/02; Object Layer Attributes #2, Jednotka: m3; Object Layer Attributes #2, Název_objektu: Plocha podlahy
 | 1.18 | SKIRTINGBOARD | FABION |  |  |  |  |  |  |  | NEW | NEMSOK - Kód prvku: PD00.03.0000; Práce: Povlakové podlahy; Faktor: 1; Materiál: FABION; Vztažná_výška: 0; Delta_výšky: 0; Allright_Stavebni_dil_ID: 1469Liš0000002885; Jednotka: m; Název_objektu: Lišta
 | 1.18 | CEILING | RASTR 1 0.03 m | 1 | 0.03 | 0 | 1 | 1469Dpl0000001133/01 | m3 | Plocha stropu | NEW | 13.239 | 0.03 | 0 | NEMSOK - Object Layer Attributes #1, Kód prvku: PH03.03.1001; Object Layer Attributes #1, Práce: Suché stavební práce; Object Layer Attributes #1, Materiál: RASTR 1; Object Layer Attributes #1, Výška svěšení: 0.6 m; Object Layer Attributes #1, Únosnost bodová: 0.5 kg; Pset_CoveringCommon - Flammability: bez požadavku
 | 1.19 | FLOORING | layer 0.295 m, PŘÍRODNÍ LINOLEUM 0.005 m | 1 | 0.295 | 0 | 1 | 1469Ppl0000001143/01 | m3 | Plocha podlahy | NEW | 11.271 | 0.3 | 0 | NEMSOK - Object Layer Attributes #2, Status: Nový; Object Layer Attributes #2, Kód prvku: PD06.03.0001; Object Layer Attributes #2, Práce: Povlakové podlahy; Object Layer Attributes #2, Číslo_vrstvy: 2; Object Layer Attributes #2, Tloušťka_vrstvy: 0.005 m; Object Layer Attributes #2, Tloušťka: 0 m; Object Layer Attributes #2, Faktor: 1; Object Layer Attributes #2, Označení: I.P5; Object Layer Attributes #2, Materiál: PŘÍRODNÍ LINOLEUM; Object Layer Attributes #2, Vztažná_výška: 0; Object Layer Attributes #2, Delta_výšky: 0; Object Layer Attributes #2, Podlaží: 1.NP; Object Layer Attributes #2, Číslo místnosti: 1.19; Object Layer Attributes #2, Plošná únosnost: 5; Object Layer Attributes #2, Allright_Stavebni_dil_ID: 1469Ppl0000001143/02; Object Layer Attributes #2, Jednotka: m3; Object Layer Attributes #2, Název_objektu: Plocha podlahy
 | 1.19 | SKIRTINGBOARD | FABION |  |  |  |  |  |  |  | NEW | NEMSOK - Kód prvku: PD00.03.0000; Práce: Povlakové podlahy; Faktor: 1; Materiál: FABION; Vztažná_výška: 0; Delta_výšky: 0; Allright_Stavebni_dil_ID: 1469Liš0000002886; Jednotka: m; Název_objektu: Lišta
 | 1.19 | CEILING | RASTR 1 0.03 m | 1 | 0.03 | 0 | 1 | 1469Dpl0000001142/01 | m3 | Plocha stropu | NEW | 11.271 | 0.03 | 0 | NEMSOK - Object Layer Attributes #1, Kód prvku: PH03.03.1001; Object Layer Attributes #1, Práce: Suché stavební práce; Object Layer Attributes #1, Materiál: RASTR 1; Object Layer Attributes #1, Výška svěšení: 0.6 m; Object Layer Attributes #1, Únosnost bodová: 0.5 kg; Pset_CoveringCommon - Flammability: bez požadavku
 | 1.20 | FLOORING | layer 0.095 m, PŘÍRODNÍ LINOLEUM 0.005 m | 1 | 0.095 | 0 | 1 | 1469Ppl0000001152/01 | m3 | Plocha podlahy | NEW | 25.994 | 0.1 | 0 | NEMSOK - Object Layer Attributes #2, Status: Nový; Object Layer Attributes #2, Kód prvku: PD06.03.0001; Object Layer Attributes #2, Práce: Povlakové podlahy; Object Layer Attributes #2, Číslo_vrstvy: 2; Object Layer Attributes #2, Tloušťka_vrstvy: 0.005 m; Object Layer Attributes #2, Tloušťka: 0 m; Object Layer Attributes #2, Faktor: 1; Object Layer Attributes #2, Označení: I.P10; Object Layer Attributes #2, Materiál: PŘÍRODNÍ LINOLEUM; Object Layer Attributes #2, Vztažná_výška: 0; Object Layer Attributes #2, Delta_výšky: 0; Object Layer Attributes #2, Podlaží: 1.NP; Object Layer Attributes #2, Číslo místnosti: 1.20; Object Layer Attributes #2, Plošná únosnost: 3; Object Layer Attributes #2, Allright_Stavebni_dil_ID: 1469Ppl0000001152/02; Object Layer Attributes #2, Jednotka: m3; Object Layer Attributes #2, Název_objektu: Plocha podlahy; Object Layer Attributes #2, Kročejová neprůzvučnost: 41
 | 1.20 | SKIRTINGBOARD | FABION |  |  |  |  |  |  |  | NEW | NEMSOK - Kód prvku: PD00.03.0000; Práce: Povlakové podlahy; Faktor: 1; Materiál: FABION; Vztažná_výška: 0; Delta_výšky: 0; Allright_Stavebni_dil_ID: 1469Liš0000002890; Jednotka: m; Název_objektu: Lišta; Plošná únosnost: 3
 | 1.20 | CEILING | RASTR 3 0.03 m | 1 | 0.03 | 0 | 1 | 1469Dpl0000001151/01 | m3 | Plocha stropu | NEW | 25.994 | 0.03 | 0 | NEMSOK - Object Layer Attributes #1, Kód prvku: PH03.03.3001; Object Layer Attributes #1, Práce: Suché stavební práce; Object Layer Attributes #1, Materiál: RASTR 3; Object Layer Attributes #1, Výška svěšení: 0.45 m; Object Layer Attributes #1, Únosnost bodová: 0.5 kg; Pset_CoveringCommon - Flammability: bez požadavku
 | 1.21 | FLOORING | layer 0.085 m, KERAMICKÁ DLAŽBA 0.015 m | 1 | 0.085 | 0 | 1 | 1469Ppl0000001161/01 | m3 | Plocha podlahy | NEW | 3.737 | 0.1 | 0 | NEMSOK - Object Layer Attributes #2, Status: Nový; Object Layer Attributes #2, Kód prvku: PD01.03.0001; Object Layer Attributes #2, Práce: Obklady a dlažby; Object Layer Attributes #2, Číslo_vrstvy: 2; Object Layer Attributes #2, Tloušťka_vrstvy: 0.015 m; Object Layer Attributes #2, Tloušťka: 0 m; Object Layer Attributes #2, Faktor: 1; Object Layer Attributes #2, Označení: I.P12; Object Layer Attributes #2, Materiál: KERAMICKÁ DLAŽBA; Object Layer Attributes #2, Vztažná_výška: 0; Object Layer Attributes #2, Delta_výšky: 0; Object Layer Attributes #2, Podlaží: 1.NP; Object Layer Attributes #2, Číslo místnosti: 1.21; Object Layer Attributes #2, Plošná únosnost: 3; Object Layer Attributes #2, Allright_Stavebni_dil_ID: 1469Ppl0000001161/02; Object Layer Attributes #2, Jednotka: m3; Object Layer Attributes #2, Název_objektu: Plocha podlahy; Object Layer Attributes #2, Kročejová neprůzvučnost: 42.5
 | 1.21 | CEILING | RASTR 2 0.03 m | 1 | 0.03 | 0 | 1 | 1469Dpl0000001160/01 | m3 | Plocha stropu | NEW | 3.737 | 0.03 | 0 | NEMSOK - Object Layer Attributes #1, Kód prvku: PH03.03.2001; Object Layer Attributes #1, Práce: Suché stavební práce; Object Layer Attributes #1, Materiál: RASTR 2; Object Layer Attributes #1, Výška svěšení: 0.65 m; Object Layer Attributes #1, Únosnost bodová: 0.5 kg; Pset_CoveringCommon - Flammability: bez požadavku
 | 1.22 | FLOORING | layer 0.085 m, KERAMICKÁ DLAŽBA 0.015 m | 1 | 0.085 | 0 | 1 | 1469Ppl0000001179/01 | m3 | Plocha podlahy | NEW | 3.348 | 0.1 | 0 | NEMSOK - Object Layer Attributes #2, Status: Nový; Object Layer Attributes #2, Kód prvku: PD01.03.0001; Object Layer Attributes #2, Práce: Obklady a dlažby; Object Layer Attributes #2, Číslo_vrstvy: 2; Object Layer Attributes #2, Tloušťka_vrstvy: 0.015 m; Object Layer Attributes #2, Tloušťka: 0 m; Object Layer Attributes #2, Faktor: 1; Object Layer Attributes #2, Označení: I.P12; Object Layer Attributes #2, Materiál: KERAMICKÁ DLAŽBA; Object Layer Attributes #2, Vztažná_výška: 0; Object Layer Attributes #2, Delta_výšky: 0; Object Layer Attributes #2, Podlaží: 1.NP; Object Layer Attributes #2, Číslo místnosti: 1.22; Object Layer Attributes #2, Plošná únosnost: 3; Object Layer Attributes #2, Allright_Stavebni_dil_ID: 1469Ppl0000001179/02; Object Layer Attributes #2, Jednotka: m3; Object Layer Attributes #2, Název_objektu: Plocha podlahy; Object Layer Attributes #2, Kročejová neprůzvučnost: 42.5
 | 1.22 | CEILING | RASTR 2 0.03 m | 1 | 0.03 | 0 | 1 | 1469Dpl0000001178/01 | m3 | Plocha stropu | NEW | 3.348 | 0.03 | 0 | NEMSOK - Object Layer Attributes #1, Kód prvku: PH03.03.2001; Object Layer Attributes #1, Práce: Suché stavební práce; Object Layer Attributes #1, Materiál: RASTR 2; Object Layer Attributes #1, Výška svěšení: 0.65 m; Object Layer Attributes #1, Únosnost bodová: 0.5 kg; Pset_CoveringCommon - Flammability: bez požadavku
 | 1.23 | FLOORING | layer 0.085 m, KERAMICKÁ DLAŽBA 0.015 m | 1 | 0.085 | 0 | 1 | 1469Ppl0000001197/01 | m3 | Plocha podlahy | NEW | 2.754 | 0.1 | 0 | NEMSOK - Object Layer Attributes #2, Status: Nový; Object Layer Attributes #2, Kód prvku: PD01.03.0001; Object Layer Attributes #2, Práce: Obklady a dlažby; Object Layer Attributes #2, Číslo_vrstvy: 2; Object Layer Attributes #2, Tloušťka_vrstvy: 0.015 m; Object Layer Attributes #2, Tloušťka: 0 m; Object Layer Attributes #2, Faktor: 1; Object Layer Attributes #2, Označení: I.P12; Object Layer Attributes #2, Materiál: KERAMICKÁ DLAŽBA; Object Layer Attributes #2, Vztažná_výška: 0; Object Layer Attributes #2, Delta_výšky: 0; Object Layer Attributes #2, Podlaží: 1.NP; Object Layer Attributes #2, Číslo místnosti: 1.23; Object Layer Attributes #2, Plošná únosnost: 3; Object Layer Attributes #2, Allright_Stavebni_dil_ID: 1469Ppl0000001197/02; Object Layer Attributes #2, Jednotka: m3; Object Layer Attributes #2, Název_objektu: Plocha podlahy; Object Layer Attributes #2, Kročejová neprůzvučnost: 42.5
 | 1.23 | CEILING | RASTR 2 0.03 m | 1 | 0.03 | 0 | 1 | 1469Dpl0000001196/01 | m3 | Plocha stropu | NEW | 2.754 | 0.03 | 0 | NEMSOK - Object Layer Attributes #1, Kód prvku: PH03.03.2001; Object Layer Attributes #1, Práce: Suché stavební práce; Object Layer Attributes #1, Materiál: RASTR 2; Object Layer Attributes #1, Výška svěšení: 0.65 m; Object Layer Attributes #1, Únosnost bodová: 0.5 kg; Pset_CoveringCommon - Flammability: bez požadavku
 | 1.04 | FLOORING | layer 0.095 m, PŘÍRODNÍ LINOLEUM 0.005 m | 1 | 0.095 | 0 | 1 | 1469Ppl0000001208/01 | m3 | Plocha podlahy | NEW | 22.131 | 0.1 | 0 | NEMSOK - Object Layer Attributes #2, Status: Nový; Object Layer Attributes #2, Kód prvku: PD06.03.0001; Object Layer Attributes #2, Práce: Povlakové podlahy; Object Layer Attributes #2, Číslo_vrstvy: 2; Object Layer Attributes #2, Tloušťka_vrstvy: 0.005 m; Object Layer Attributes #2, Tloušťka: 0 m; Object Layer Attributes #2, Faktor: 1; Object Layer Attributes #2, Označení: I.P10; Object Layer Attributes #2, Materiál: PŘÍRODNÍ LINOLEUM; Object Layer Attributes #2, Vztažná_výška: 0; Object Layer Attributes #2, Delta_výšky: 0; Object Layer Attributes #2, Podlaží: 1.NP; Object Layer Attributes #2, Číslo místnosti: 1.04; Object Layer Attributes #2, Plošná únosnost: 3; Object Layer Attributes #2, Allright_Stavebni_dil_ID: 1469Ppl0000001208/02; Object Layer Attributes #2, Jednotka: m3; Object Layer Attributes #2, Název_objektu: Plocha podlahy; Object Layer Attributes #2, Kročejová neprůzvučnost: 41
 | 1.04 | SKIRTINGBOARD | FABION |  |  |  |  |  |  |  | NEW | NEMSOK - Kód prvku: PD00.03.0000; Práce: Povlakové podlahy; Faktor: 1; Materiál: FABION; Vztažná_výška: 0; Delta_výšky: 0; Allright_Stavebni_dil_ID: 1469Liš0000002867; Jednotka: m; Název_objektu: Lišta
 | 1.04 | CEILING | RASTR 1 0.03 m | 1 | 0.03 | 0 | 1 | 1469Dpl0000001207/01 | m3 | Plocha stropu | NEW | 22.131 | 0.03 | 0 | NEMSOK - Object Layer Attributes #1, Kód prvku: PH03.03.1001; Object Layer Attributes #1, Práce: Suché stavební práce; Object Layer Attributes #1, Materiál: RASTR 1; Object Layer Attributes #1, Výška svěšení: 0.65 m; Object Layer Attributes #1, Únosnost bodová: 0.5 kg; Pset_CoveringCommon - Flammability: bez požadavku
 | 1.05 | FLOORING | layer 0.095 m, ELEKTROSTATICKÝ VINYL 0.005 m | 1 | 0.095 | 0 | 1 | 1469Ppl0000001219/01 | m3 | Plocha podlahy | NEW | 25.261 | 0.1 | 0 | NEMSOK - Object Layer Attributes #2, Status: Nový; Object Layer Attributes #2, Kód prvku: PD06.03.1001; Object Layer Attributes #2, Práce: Povlakové podlahy; Object Layer Attributes #2, Číslo_vrstvy: 2; Object Layer Attributes #2, Tloušťka_vrstvy: 0.005 m; Object Layer Attributes #2, Tloušťka: 0 m; Object Layer Attributes #2, Faktor: 1; Object Layer Attributes #2, Označení: I.P11; Object Layer Attributes #2, Materiál: ELEKTROSTATICKÝ VINYL; Object Layer Attributes #2, Vztažná_výška: 0; Object Layer Attributes #2, Delta_výšky: 0; Object Layer Attributes #2, Podlaží: 1.NP; Object Layer Attributes #2, Číslo místnosti: 1.05; Object Layer Attributes #2, Plošná únosnost: 3; Object Layer Attributes #2, Allright_Stavebni_dil_ID: 1469Ppl0000001219/02; Object Layer Attributes #2, Jednotka: m3; Object Layer Attributes #2, Název_objektu: Plocha podlahy; Object Layer Attributes #2, Kročejová neprůzvučnost: 41
 | 1.05 | SKIRTINGBOARD | FABION |  |  |  |  |  |  |  | NEW | NEMSOK - Kód prvku: PD00.03.0000; Práce: Povlakové podlahy; Faktor: 1; Materiál: FABION; Vztažná_výška: 0; Delta_výšky: 0; Allright_Stavebni_dil_ID: 1469Liš0000002870; Jednotka: m; Název_objektu: Lišta
 | 1.05 | CEILING | RASTR 3 0.03 m | 1 | 0.03 | 0 | 1 | 1469Dpl0000001218/01 | m3 | Plocha stropu | NEW | 25.261 | 0.03 | 0 | NEMSOK - Object Layer Attributes #1, Kód prvku: PH03.03.3001; Object Layer Attributes #1, Práce: Suché stavební práce; Object Layer Attributes #1, Materiál: RASTR 3; Object Layer Attributes #1, Výška svěšení: 0.65 m; Object Layer Attributes #1, Únosnost bodová: 0.5 kg; Pset_CoveringCommon - Flammability: bez požadavku
 | 1.06 | FLOORING | layer 0.085 m, KERAMICKÁ DLAŽBA 0.015 m | 1 | 0.085 | 0 | 1 | 1469Ppl0000001228/01 | m3 | Plocha podlahy | NEW | 16.342 | 0.1 | 0 | NEMSOK - Object Layer Attributes #2, Status: Nový; Object Layer Attributes #2, Kód prvku: PD01.03.0001; Object Layer Attributes #2, Práce: Obklady a dlažby; Object Layer Attributes #2, Číslo_vrstvy: 2; Object Layer Attributes #2, Tloušťka_vrstvy: 0.015 m; Object Layer Attributes #2, Tloušťka: 0 m; Object Layer Attributes #2, Faktor: 1; Object Layer Attributes #2, Označení: I.P12; Object Layer Attributes #2, Materiál: KERAMICKÁ DLAŽBA; Object Layer Attributes #2, Vztažná_výška: 0; Object Layer Attributes #2, Delta_výšky: 0; Object Layer Attributes #2, Podlaží: 1.NP; Object Layer Attributes #2, Číslo místnosti: 1.06; Object Layer Attributes #2, Plošná únosnost: 3; Object Layer Attributes #2, Allright_Stavebni_dil_ID: 1469Ppl0000001228/02; Object Layer Attributes #2, Jednotka: m3; Object Layer Attributes #2, Název_objektu: Plocha podlahy; Object Layer Attributes #2, Kročejová neprůzvučnost: 42.5
 | 1.06 | CEILING | RASTR 4 0.03 m | 1 | 0.03 | 0 | 1 | 1469Dpl0000001227/01 | m3 | Plocha stropu | NEW | 16.342 | 0.03 | 0 | NEMSOK - Object Layer Attributes #1, Kód prvku: PH03.03.4001; Object Layer Attributes #1, Práce: Suché stavební práce; Object Layer Attributes #1, Materiál: RASTR 4; Object Layer Attributes #1, Výška svěšení: 0.65 m; Object Layer Attributes #1, Únosnost bodová: 0.5 kg; Pset_CoveringCommon - Flammability: bez požadavku
 | 1.07 | FLOORING | layer 0.095 m, PŘÍRODNÍ LINOLEUM 0.005 m | 1 | 0.095 | 0 | 1 | 1469Ppl0000001237/01 | m3 | Plocha podlahy | NEW | 15.989 | 0.1 | 0 | NEMSOK - Object Layer Attributes #2, Status: Nový; Object Layer Attributes #2, Kód prvku: PD06.03.0001; Object Layer Attributes #2, Práce: Povlakové podlahy; Object Layer Attributes #2, Číslo_vrstvy: 2; Object Layer Attributes #2, Tloušťka_vrstvy: 0.005 m; Object Layer Attributes #2, Tloušťka: 0 m; Object Layer Attributes #2, Faktor: 1; Object Layer Attributes #2, Označení: I.P10; Object Layer Attributes #2, Materiál: PŘÍRODNÍ LINOLEUM; Object Layer Attributes #2, Vztažná_výška: 0; Object Layer Attributes #2, Delta_výšky: 0; Object Layer Attributes #2, Podlaží: 1.NP; Object Layer Attributes #2, Číslo místnosti: 1.07; Object Layer Attributes #2, Plošná únosnost: 3; Object Layer Attributes #2, Allright_Stavebni_dil_ID: 1469Ppl0000001237/02; Object Layer Attributes #2, Jednotka: m3; Object Layer Attributes #2, Název_objektu: Plocha podlahy; Object Layer Attributes #2, Kročejová neprůzvučnost: 41
 | 1.07 | SKIRTINGBOARD | SOKLOVÁ PVC LIŠTA |  |  |  |  |  |  |  | NEW | NEMSOK - Kód prvku: PD00.03.0000; Práce: Povlakové podlahy; Faktor: 1; Materiál: SOKLOVÁ PVC LIŠTA; Vztažná_výška: 0; Delta_výšky: 0; Allright_Stavebni_dil_ID: 1469Liš0000002871; Jednotka: m; Název_objektu: Lišta
 | 1.07 | CEILING | RASTR 2 0.03 m | 1 | 0.03 | 0 | 1 | 1469Dpl0000001236/01 | m3 | Plocha stropu | NEW | 15.989 | 0.03 | 0 | NEMSOK - Object Layer Attributes #1, Kód prvku: PH03.03.2001; Object Layer Attributes #1, Práce: Suché stavební práce; Object Layer Attributes #1, Materiál: RASTR 2; Object Layer Attributes #1, Výška svěšení: 0.65 m; Object Layer Attributes #1, Únosnost bodová: 0.5 kg; Pset_CoveringCommon - Flammability: bez požadavku
 | 1.27 | FLOORING | layer 0.095 m, PŘÍRODNÍ LINOLEUM 0.005 m | 1 | 0.095 | 0 | 1 | 1469Ppl0000001246/01 | m3 | Plocha podlahy | NEW | 28.369 | 0.1 | 0 | NEMSOK - Object Layer Attributes #2, Status: Nový; Object Layer Attributes #2, Kód prvku: PD06.03.0001; Object Layer Attributes #2, Práce: Povlakové podlahy; Object Layer Attributes #2, Číslo_vrstvy: 2; Object Layer Attributes #2, Tloušťka_vrstvy: 0.005 m; Object Layer Attributes #2, Tloušťka: 0 m; Object Layer Attributes #2, Faktor: 1; Object Layer Attributes #2, Označení: I.P10; Object Layer Attributes #2, Materiál: PŘÍRODNÍ LINOLEUM; Object Layer Attributes #2, Vztažná_výška: 0; Object Layer Attributes #2, Delta_výšky: 0; Object Layer Attributes #2, Podlaží: 1.NP; Object Layer Attributes #2, Číslo místnosti: 1.27; Object Layer Attributes #2, Plošná únosnost: 3; Object Layer Attributes #2, Allright_Stavebni_dil_ID: 1469Ppl0000001246/02; Object Layer Attributes #2, Jednotka: m3; Object Layer Attributes #2, Název_objektu: Plocha podlahy; Object Layer Attributes #2, Kročejová neprůzvučnost: 41
 | 1.27 | SKIRTINGBOARD | FABION |  |  |  |  |  |  |  | NEW | NEMSOK - Kód prvku: PD00.03.0000; Práce: Povlakové podlahy; Faktor: 1; Materiál: FABION; Vztažná_výška: 0; Delta_výšky: 0; Allright_Stavebni_dil_ID: 1469Liš0000002888; Jednotka: m; Název_objektu: Lišta
 | 1.27 | CEILING | RASTR 2 0.03 m | 1 | 0.03 | 0 | 1 | 1469Dpl0000001245/01 | m3 | Plocha stropu | NEW | 28.369 | 0.03 | 0 | NEMSOK - Object Layer Attributes #1, Kód prvku: PH03.03.2001; Object Layer Attributes #1, Práce: Suché stavební práce; Object Layer Attributes #1, Materiál: RASTR 2; Object Layer Attributes #1, Výška svěšení: 0.65 m; Object Layer Attributes #1, Únosnost bodová: 0.5 kg; Pset_CoveringCommon - Flammability: bez požadavku
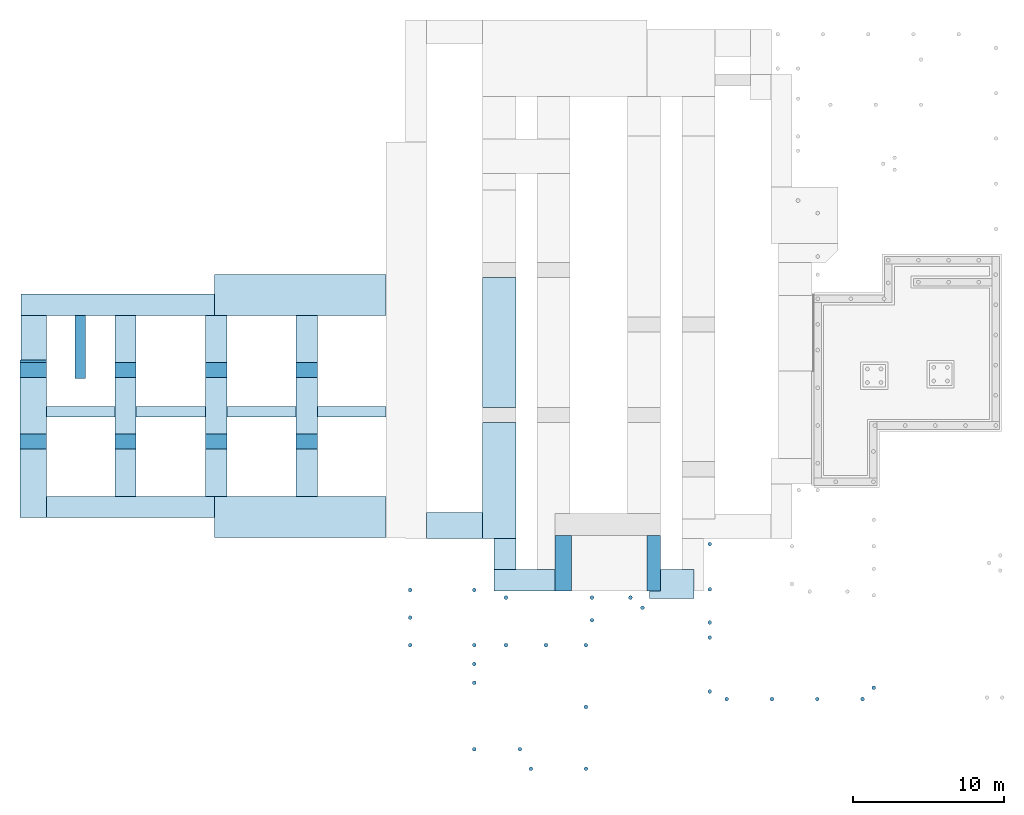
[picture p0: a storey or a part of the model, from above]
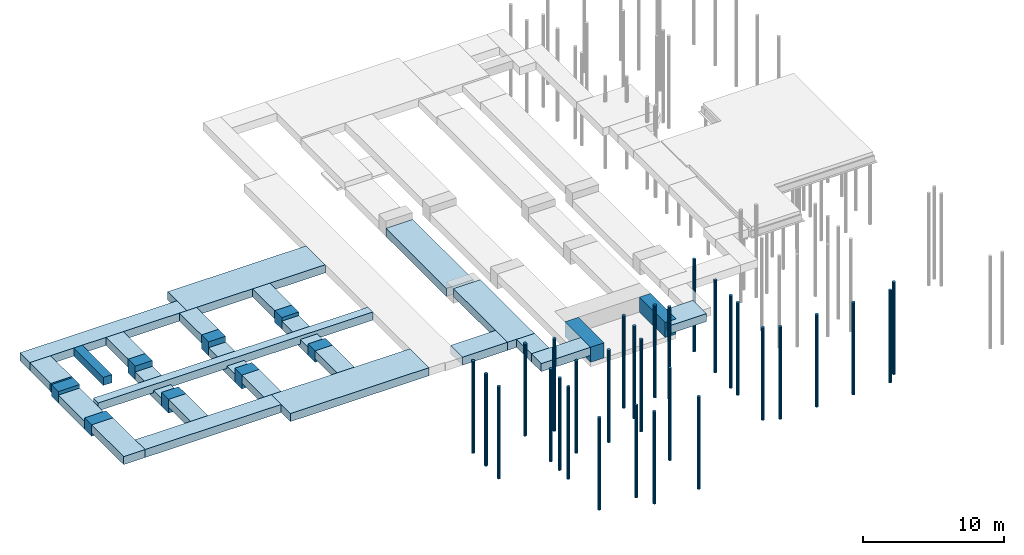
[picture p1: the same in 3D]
Properties of the parts of a building model (IFC4), part 8 of 45

# IfcCovering (314)
Name | In | PredefinedType | Material | Object Layer Attributes #1, Číslo_vrstvy | Object Layer Attributes #1, Tloušťka_vrstvy (m) | Object Layer Attributes #1, Tloušťka (m) = Object Layer Attributes #1, Vztažná_výška = Object Layer Attributes #1, Delta_výšky | Object Layer Attributes #1, Faktor | Object Layer Attributes #1, Allright_Stavebni_dil_ID | Object Layer Attributes #1, Jednotka | Object Layer Attributes #1, Název_objektu | Status | NetArea (m2) | Width (m) | Perimeter (m)
 | 1.28 | FLOORING | layer 0.085 m, KERAMICKÁ DLAŽBA 0.015 m | 1 | 0.085 | 0 | 1 | 1469Ppl0000001255/01 | m3 | Plocha podlahy | NEW | 2.291 | 0.1 | 0 | NEMSOK - Object Layer Attributes #2, Status: Nový; Object Layer Attributes #2, Kód prvku: PD01.03.0001; Object Layer Attributes #2, Práce: Obklady a dlažby; Object Layer Attributes #2, Číslo_vrstvy: 2; Object Layer Attributes #2, Tloušťka_vrstvy: 0.015 m; Object Layer Attributes #2, Tloušťka: 0 m; Object Layer Attributes #2, Faktor: 1; Object Layer Attributes #2, Označení: I.P12; Object Layer Attributes #2, Materiál: KERAMICKÁ DLAŽBA; Object Layer Attributes #2, Vztažná_výška: 0; Object Layer Attributes #2, Delta_výšky: 0; Object Layer Attributes #2, Podlaží: 1.NP; Object Layer Attributes #2, Číslo místnosti: 1.28; Object Layer Attributes #2, Plošná únosnost: 3; Object Layer Attributes #2, Allright_Stavebni_dil_ID: 1469Ppl0000001255/02; Object Layer Attributes #2, Jednotka: m3; Object Layer Attributes #2, Název_objektu: Plocha podlahy; Object Layer Attributes #2, Kročejová neprůzvučnost: 42.5
 | 1.28 | CEILING | RASTR 2 0.03 m | 1 | 0.03 | 0 | 1 | 1469Dpl0000001254/01 | m3 | Plocha stropu | NEW | 2.291 | 0.03 | 0 | NEMSOK - Object Layer Attributes #1, Kód prvku: PH03.03.2001; Object Layer Attributes #1, Práce: Suché stavební práce; Object Layer Attributes #1, Materiál: RASTR 2; Object Layer Attributes #1, Výška svěšení: 0.65 m; Object Layer Attributes #1, Únosnost bodová: 0.5 kg; Pset_CoveringCommon - Flammability: bez požadavku
 | 1.28a | FLOORING | layer 0.085 m, KERAMICKÁ DLAŽBA 0.015 m | 1 | 0.085 | 0 | 1 | 1469Ppl0000001264/01 | m3 | Plocha podlahy | NEW | 2.21 | 0.1 | 0 | NEMSOK - Object Layer Attributes #2, Status: Nový; Object Layer Attributes #2, Kód prvku: PD01.03.0001; Object Layer Attributes #2, Práce: Obklady a dlažby; Object Layer Attributes #2, Číslo_vrstvy: 2; Object Layer Attributes #2, Tloušťka_vrstvy: 0.015 m; Object Layer Attributes #2, Tloušťka: 0 m; Object Layer Attributes #2, Faktor: 1; Object Layer Attributes #2, Označení: I.P12; Object Layer Attributes #2, Materiál: KERAMICKÁ DLAŽBA; Object Layer Attributes #2, Vztažná_výška: 0; Object Layer Attributes #2, Delta_výšky: 0; Object Layer Attributes #2, Podlaží: 1.NP; Object Layer Attributes #2, Číslo místnosti: 1.28a; Object Layer Attributes #2, Plošná únosnost: 3; Object Layer Attributes #2, Allright_Stavebni_dil_ID: 1469Ppl0000001264/02; Object Layer Attributes #2, Jednotka: m3; Object Layer Attributes #2, Název_objektu: Plocha podlahy; Object Layer Attributes #2, Kročejová neprůzvučnost: 42.5
 | 1.28a | CEILING | RASTR 2 0.03 m | 1 | 0.03 | 0 | 1 | 1469Dpl0000001263/01 | m3 | Plocha stropu | NEW | 2.21 | 0.03 | 0 | NEMSOK - Object Layer Attributes #1, Kód prvku: PH03.03.2001; Object Layer Attributes #1, Práce: Suché stavební práce; Object Layer Attributes #1, Materiál: RASTR 2; Object Layer Attributes #1, Výška svěšení: 0.65 m; Object Layer Attributes #1, Únosnost bodová: 0.5 kg; Pset_CoveringCommon - Flammability: bez požadavku
 | 1.28b | FLOORING | layer 0.085 m, KERAMICKÁ DLAŽBA 0.015 m | 1 | 0.085 | 0 | 1 | 1469Ppl0000001273/01 | m3 | Plocha podlahy | NEW | 1.95 | 0.1 | 0 | NEMSOK - Object Layer Attributes #2, Status: Nový; Object Layer Attributes #2, Kód prvku: PD01.03.0001; Object Layer Attributes #2, Práce: Obklady a dlažby; Object Layer Attributes #2, Číslo_vrstvy: 2; Object Layer Attributes #2, Tloušťka_vrstvy: 0.015 m; Object Layer Attributes #2, Tloušťka: 0 m; Object Layer Attributes #2, Faktor: 1; Object Layer Attributes #2, Označení: I.P12; Object Layer Attributes #2, Materiál: KERAMICKÁ DLAŽBA; Object Layer Attributes #2, Vztažná_výška: 0; Object Layer Attributes #2, Delta_výšky: 0; Object Layer Attributes #2, Podlaží: 1.NP; Object Layer Attributes #2, Číslo místnosti: 1.28b; Object Layer Attributes #2, Plošná únosnost: 3; Object Layer Attributes #2, Allright_Stavebni_dil_ID: 1469Ppl0000001273/02; Object Layer Attributes #2, Jednotka: m3; Object Layer Attributes #2, Název_objektu: Plocha podlahy; Object Layer Attributes #2, Kročejová neprůzvučnost: 42.5
 | 1.28b | CEILING | RASTR 4 0.03 m | 1 | 0.03 | 0 | 1 | 1469Dpl0000001272/01 | m3 | Plocha stropu | NEW | 1.95 | 0.03 | 0 | NEMSOK - Object Layer Attributes #1, Kód prvku: PH03.03.4001; Object Layer Attributes #1, Práce: Suché stavební práce; Object Layer Attributes #1, Materiál: RASTR 4; Object Layer Attributes #1, Výška svěšení: 0.65 m; Object Layer Attributes #1, Únosnost bodová: 0.5 kg; Pset_CoveringCommon - Flammability: bez požadavku
 | 1.25 | FLOORING | layer 0.095 m, PŘÍRODNÍ LINOLEUM 0.005 m | 1 | 0.095 | 0 | 1 | 1469Ppl0000001282/01 | m3 | Plocha podlahy | NEW | 11.862 | 0.1 | 0 | NEMSOK - Object Layer Attributes #2, Status: Nový; Object Layer Attributes #2, Kód prvku: PD06.03.0001; Object Layer Attributes #2, Práce: Povlakové podlahy; Object Layer Attributes #2, Číslo_vrstvy: 2; Object Layer Attributes #2, Tloušťka_vrstvy: 0.005 m; Object Layer Attributes #2, Tloušťka: 0 m; Object Layer Attributes #2, Faktor: 1; Object Layer Attributes #2, Označení: I.P10; Object Layer Attributes #2, Materiál: PŘÍRODNÍ LINOLEUM; Object Layer Attributes #2, Vztažná_výška: 0; Object Layer Attributes #2, Delta_výšky: 0; Object Layer Attributes #2, Podlaží: 1.NP; Object Layer Attributes #2, Číslo místnosti: 1.25; Object Layer Attributes #2, Plošná únosnost: 3; Object Layer Attributes #2, Allright_Stavebni_dil_ID: 1469Ppl0000001282/02; Object Layer Attributes #2, Jednotka: m3; Object Layer Attributes #2, Název_objektu: Plocha podlahy; Object Layer Attributes #2, Kročejová neprůzvučnost: 41
 | 1.25 | SKIRTINGBOARD | FABION |  |  |  |  |  |  |  | NEW | NEMSOK - Kód prvku: PD00.03.0000; Práce: Povlakové podlahy; Faktor: 1; Materiál: FABION; Vztažná_výška: 0; Delta_výšky: 0; Allright_Stavebni_dil_ID: 1469Liš0000002889; Jednotka: m; Název_objektu: Lišta
 | 1.25 | CEILING | RASTR 2 0.03 m | 1 | 0.03 | 0 | 1 | 1469Dpl0000001281/01 | m3 | Plocha stropu | NEW | 11.862 | 0.03 | 0 | NEMSOK - Object Layer Attributes #1, Kód prvku: PH03.03.2001; Object Layer Attributes #1, Práce: Suché stavební práce; Object Layer Attributes #1, Materiál: RASTR 2; Object Layer Attributes #1, Výška svěšení: 0.65 m; Object Layer Attributes #1, Únosnost bodová: 0.5 kg; Pset_CoveringCommon - Flammability: bez požadavku
 | 1.26 | FLOORING | layer 0.085 m, KERAMICKÁ DLAŽBA 0.015 m | 1 | 0.085 | 0 | 1 | 1469Ppl0000001293/01 | m3 | Plocha podlahy | NEW | 2.913 | 0.1 | 0 | NEMSOK - Object Layer Attributes #2, Status: Nový; Object Layer Attributes #2, Kód prvku: PD01.03.0001; Object Layer Attributes #2, Práce: Obklady a dlažby; Object Layer Attributes #2, Číslo_vrstvy: 2; Object Layer Attributes #2, Tloušťka_vrstvy: 0.015 m; Object Layer Attributes #2, Tloušťka: 0 m; Object Layer Attributes #2, Faktor: 1; Object Layer Attributes #2, Označení: I.P12; Object Layer Attributes #2, Materiál: KERAMICKÁ DLAŽBA; Object Layer Attributes #2, Vztažná_výška: 0; Object Layer Attributes #2, Delta_výšky: 0; Object Layer Attributes #2, Podlaží: 1.NP; Object Layer Attributes #2, Číslo místnosti: 1.26; Object Layer Attributes #2, Plošná únosnost: 3; Object Layer Attributes #2, Allright_Stavebni_dil_ID: 1469Ppl0000001293/02; Object Layer Attributes #2, Jednotka: m3; Object Layer Attributes #2, Název_objektu: Plocha podlahy; Object Layer Attributes #2, Kročejová neprůzvučnost: 42.5
 | 1.26 | CEILING | RASTR 4 0.03 m | 1 | 0.03 | 0 | 1 | 1469Dpl0000001292/01 | m3 | Plocha stropu | NEW | 2.913 | 0.03 | 0 | NEMSOK - Object Layer Attributes #1, Kód prvku: PH03.03.4001; Object Layer Attributes #1, Práce: Suché stavební práce; Object Layer Attributes #1, Materiál: RASTR 4; Object Layer Attributes #1, Výška svěšení: 0.65 m; Object Layer Attributes #1, Únosnost bodová: 0.5 kg; Pset_CoveringCommon - Flammability: bez požadavku
 | 1.26a | FLOORING | layer 0.085 m, KERAMICKÁ DLAŽBA 0.015 m | 1 | 0.085 | 0 | 1 | 1469Ppl0000001302/01 | m3 | Plocha podlahy | NEW | 1.058 | 0.1 | 0 | NEMSOK - Object Layer Attributes #2, Status: Nový; Object Layer Attributes #2, Kód prvku: PD01.03.0001; Object Layer Attributes #2, Práce: Obklady a dlažby; Object Layer Attributes #2, Číslo_vrstvy: 2; Object Layer Attributes #2, Tloušťka_vrstvy: 0.015 m; Object Layer Attributes #2, Tloušťka: 0 m; Object Layer Attributes #2, Faktor: 1; Object Layer Attributes #2, Označení: I.P12; Object Layer Attributes #2, Materiál: KERAMICKÁ DLAŽBA; Object Layer Attributes #2, Vztažná_výška: 0; Object Layer Attributes #2, Delta_výšky: 0; Object Layer Attributes #2, Podlaží: 1.NP; Object Layer Attributes #2, Číslo místnosti: 1.26a; Object Layer Attributes #2, Plošná únosnost: 3; Object Layer Attributes #2, Allright_Stavebni_dil_ID: 1469Ppl0000001302/02; Object Layer Attributes #2, Jednotka: m3; Object Layer Attributes #2, Název_objektu: Plocha podlahy; Object Layer Attributes #2, Kročejová neprůzvučnost: 42.5
 | 1.26a | CEILING | RASTR 2 0.03 m | 1 | 0.03 | 0 | 1 | 1469Dpl0000001301/01 | m3 | Plocha stropu | NEW | 1.058 | 0.03 | 0 | NEMSOK - Object Layer Attributes #1, Kód prvku: PH03.03.2001; Object Layer Attributes #1, Práce: Suché stavební práce; Object Layer Attributes #1, Materiál: RASTR 2; Object Layer Attributes #1, Výška svěšení: 0.65 m; Object Layer Attributes #1, Únosnost bodová: 0.5 kg; Pset_CoveringCommon - Flammability: bez požadavku
 | 1.30 | FLOORING | layer 0.095 m, PŘÍRODNÍ LINOLEUM 0.005 m | 1 | 0.095 | 0 | 1 | 1469Ppl0000001311/01 | m3 | Plocha podlahy | NEW | 49.32 | 0.1 | 0 | NEMSOK - Object Layer Attributes #2, Status: Nový; Object Layer Attributes #2, Kód prvku: PD06.03.0001; Object Layer Attributes #2, Práce: Povlakové podlahy; Object Layer Attributes #2, Číslo_vrstvy: 2; Object Layer Attributes #2, Tloušťka_vrstvy: 0.005 m; Object Layer Attributes #2, Tloušťka: 0 m; Object Layer Attributes #2, Faktor: 1; Object Layer Attributes #2, Označení: I.P10; Object Layer Attributes #2, Materiál: PŘÍRODNÍ LINOLEUM; Object Layer Attributes #2, Vztažná_výška: 0; Object Layer Attributes #2, Delta_výšky: 0; Object Layer Attributes #2, Podlaží: 1.NP; Object Layer Attributes #2, Číslo místnosti: 1.30; Object Layer Attributes #2, Plošná únosnost: 3; Object Layer Attributes #2, Allright_Stavebni_dil_ID: 1469Ppl0000001311/02; Object Layer Attributes #2, Jednotka: m3; Object Layer Attributes #2, Název_objektu: Plocha podlahy; Object Layer Attributes #2, Kročejová neprůzvučnost: 41
 | 1.30 | SKIRTINGBOARD | FABION |  |  |  |  |  |  |  | NEW | NEMSOK - Kód prvku: PD00.03.0000; Práce: Povlakové podlahy; Faktor: 1; Materiál: FABION; Vztažná_výška: 0; Delta_výšky: 0; Allright_Stavebni_dil_ID: 1469Liš0000002887; Jednotka: m; Název_objektu: Lišta
 | 1.30 | CEILING | RASTR 1 0.03 m | 1 | 0.03 | 0 | 1 | 1469Dpl0000001310/01 | m3 | Plocha stropu | NEW | 49.32 | 0.03 | 0 | NEMSOK - Object Layer Attributes #1, Kód prvku: PH03.03.1001; Object Layer Attributes #1, Práce: Suché stavební práce; Object Layer Attributes #1, Materiál: RASTR 1; Object Layer Attributes #1, Výška svěšení: 0.65 m; Object Layer Attributes #1, Únosnost bodová: 0.5 kg; Pset_CoveringCommon - Flammability: bez požadavku
 | 1.29 | FLOORING | layer 0.085 m, KERAMICKÁ DLAŽBA 0.015 m | 1 | 0.085 | 0 | 1 | 1469Ppl0000001322/01 | m3 | Plocha podlahy | NEW | 18.302 | 0.1 | 0 | NEMSOK - Object Layer Attributes #2, Status: Nový; Object Layer Attributes #2, Kód prvku: PD01.03.0001; Object Layer Attributes #2, Práce: Obklady a dlažby; Object Layer Attributes #2, Číslo_vrstvy: 2; Object Layer Attributes #2, Tloušťka_vrstvy: 0.015 m; Object Layer Attributes #2, Tloušťka: 0 m; Object Layer Attributes #2, Faktor: 1; Object Layer Attributes #2, Označení: I.P12; Object Layer Attributes #2, Materiál: KERAMICKÁ DLAŽBA; Object Layer Attributes #2, Vztažná_výška: 0; Object Layer Attributes #2, Delta_výšky: 0; Object Layer Attributes #2, Podlaží: 1.NP; Object Layer Attributes #2, Číslo místnosti: 1.29; Object Layer Attributes #2, Plošná únosnost: 3; Object Layer Attributes #2, Allright_Stavebni_dil_ID: 1469Ppl0000001322/02; Object Layer Attributes #2, Jednotka: m3; Object Layer Attributes #2, Název_objektu: Plocha podlahy; Object Layer Attributes #2, Kročejová neprůzvučnost: 42.5
 | 1.29 | CEILING | RASTR 4 0.03 m | 1 | 0.03 | 0 | 1 | 1469Dpl0000001321/01 | m3 | Plocha stropu | NEW | 18.302 | 0.03 | 0 | NEMSOK - Object Layer Attributes #1, Kód prvku: PH03.03.4001; Object Layer Attributes #1, Práce: Suché stavební práce; Object Layer Attributes #1, Materiál: RASTR 4; Object Layer Attributes #1, Výška svěšení: 0.65 m; Object Layer Attributes #1, Únosnost bodová: 0.5 kg; Pset_CoveringCommon - Flammability: bez požadavku
 | 1.31 | FLOORING | layer 0.095 m, ELEKTROSTATICKÝ VINYL 0.005 m | 1 | 0.095 | 0 | 1 | 1469Ppl0000001331/01 | m3 | Plocha podlahy | NEW | 6.512 | 0.1 | 0 | NEMSOK - Object Layer Attributes #2, Status: Nový; Object Layer Attributes #2, Kód prvku: PD06.03.1001; Object Layer Attributes #2, Práce: Povlakové podlahy; Object Layer Attributes #2, Číslo_vrstvy: 2; Object Layer Attributes #2, Tloušťka_vrstvy: 0.005 m; Object Layer Attributes #2, Tloušťka: 0 m; Object Layer Attributes #2, Faktor: 1; Object Layer Attributes #2, Označení: I.P11; Object Layer Attributes #2, Materiál: ELEKTROSTATICKÝ VINYL; Object Layer Attributes #2, Vztažná_výška: 0; Object Layer Attributes #2, Delta_výšky: 0; Object Layer Attributes #2, Podlaží: 1.NP; Object Layer Attributes #2, Číslo místnosti: 1.31; Object Layer Attributes #2, Plošná únosnost: 3; Object Layer Attributes #2, Allright_Stavebni_dil_ID: 1469Ppl0000001331/02; Object Layer Attributes #2, Jednotka: m3; Object Layer Attributes #2, Název_objektu: Plocha podlahy; Object Layer Attributes #2, Kročejová neprůzvučnost: 41
 | 1.31 | CEILING | SÁDROVÁ OMÍTKA 0.015 m, MALBA 0.005 m | 1 | 0.015 | 0 | 1 | 1469Dpl0000001330/01 | m3 | Plocha stropu | NEW | 6.512 | 0.02 | 0 | NEMSOK - Object Layer Attributes #1, Kód prvku: OM04.03.0001; Object Layer Attributes #1, Práce: Omítky a štuky; Object Layer Attributes #1, Materiál: SÁDROVÁ OMÍTKA; Object Layer Attributes #1, Způsob provedení: strojní; Object Layer Attributes #2, Status: Nový; Object Layer Attributes #2, Kód prvku: MB03.03.1001; Object Layer Attributes #2, Práce: Malby a nátěry; Object Layer Attributes #2, Číslo_vrstvy: 2; Object Layer Attributes #2, Tloušťka_vrstvy: 0.005 m; Object Layer Attributes #2, Tloušťka: 0 m; Object Layer Attributes #2, Faktor: 1; Object Layer Attributes #2, Materiál: MALBA; Object Layer Attributes #2, Vztažná_výška: 0; Object Layer Attributes #2, Delta_výšky: 0; Object Layer Attributes #2, Podlaží: 1.NP; Object Layer Attributes #2, Allright_Stavebni_dil_ID: 1469Dpl0000001330/02; Object Layer Attributes #2, Jednotka: m3; Object Layer Attributes #2, Název_objektu: Plocha stropu; Object Layer Attributes #2, Způsob provedení: ruční
 | 1.31 | SKIRTINGBOARD | SOKLOVÁ PVC LIŠTA |  |  |  |  |  |  |  | NEW | NEMSOK - Kód prvku: PD00.03.0000; Práce: Povlakové podlahy; Faktor: 1; Materiál: SOKLOVÁ PVC LIŠTA; Vztažná_výška: 0; Delta_výšky: 0; Allright_Stavebni_dil_ID: 1469Liš0000002872; Jednotka: m; Název_objektu: Lišta
 | 1.33 | FLOORING | layer 0.295 m, PŘÍRODNÍ LINOLEUM 0.005 m | 1 | 0.295 | 0 | 1 | 1469Ppl0000001840/01 | m3 | Plocha podlahy | NEW | 3.725 | 0.3 | 0 | NEMSOK - Object Layer Attributes #2, Status: Nový; Object Layer Attributes #2, Kód prvku: PD06.03.0001; Object Layer Attributes #2, Práce: Povlakové podlahy; Object Layer Attributes #2, Číslo_vrstvy: 2; Object Layer Attributes #2, Tloušťka_vrstvy: 0.005 m; Object Layer Attributes #2, Tloušťka: 0 m; Object Layer Attributes #2, Faktor: 1; Object Layer Attributes #2, Označení: I.P5; Object Layer Attributes #2, Materiál: PŘÍRODNÍ LINOLEUM; Object Layer Attributes #2, Vztažná_výška: 0; Object Layer Attributes #2, Delta_výšky: 0; Object Layer Attributes #2, Podlaží: 1.NP; Object Layer Attributes #2, Číslo místnosti: 1.33; Object Layer Attributes #2, Plošná únosnost: 5; Object Layer Attributes #2, Allright_Stavebni_dil_ID: 1469Ppl0000001840/02; Object Layer Attributes #2, Jednotka: m3; Object Layer Attributes #2, Název_objektu: Plocha podlahy
 | 1.33 | CEILING | SÁDROVÁ OMÍTKA 0.015 m, MALBA 0.005 m | 1 | 0.015 | 0 | 1 | 1469Dpl0000001839/01 | m3 | Plocha stropu | NEW | 3.725 | 0.02 | 0 | NEMSOK - Object Layer Attributes #1, Kód prvku: OM04.03.0001; Object Layer Attributes #1, Práce: Omítky a štuky; Object Layer Attributes #1, Materiál: SÁDROVÁ OMÍTKA; Object Layer Attributes #1, Způsob provedení: strojní; Object Layer Attributes #2, Status: Nový; Object Layer Attributes #2, Kód prvku: MB03.03.1001; Object Layer Attributes #2, Práce: Malby a nátěry; Object Layer Attributes #2, Číslo_vrstvy: 2; Object Layer Attributes #2, Tloušťka_vrstvy: 0.005 m; Object Layer Attributes #2, Tloušťka: 0 m; Object Layer Attributes #2, Faktor: 1; Object Layer Attributes #2, Materiál: MALBA; Object Layer Attributes #2, Vztažná_výška: 0; Object Layer Attributes #2, Delta_výšky: 0; Object Layer Attributes #2, Podlaží: 1.NP; Object Layer Attributes #2, Allright_Stavebni_dil_ID: 1469Dpl0000001839/02; Object Layer Attributes #2, Jednotka: m3; Object Layer Attributes #2, Název_objektu: Plocha stropu; Object Layer Attributes #2, Způsob provedení: ruční
 | 1.33 | SKIRTINGBOARD | SOKLOVÁ PVC LIŠTA |  |  |  |  |  |  |  | NEW | NEMSOK - Kód prvku: PD00.03.0000; Práce: Povlakové podlahy; Faktor: 1; Materiál: SOKLOVÁ PVC LIŠTA; Vztažná_výška: 0; Delta_výšky: 0; Allright_Stavebni_dil_ID: 1469Liš0000002865; Jednotka: m; Název_objektu: Lišta
I.P7 | 1.03 | FLOORING | layer 0.295 m, ELEKTROSTATICKÝ VINYL 0.005 m | 1 | 0.295 | 0 | 1 | 1469Ppl0000002403/01 | m3 | Plocha podlahy | NEW | 12.737 | 0.3 | 0 | NEMSOK - Object Layer Attributes #2, Status: Nový; Object Layer Attributes #2, Kód prvku: PD06.03.1001; Object Layer Attributes #2, Práce: Povlakové podlahy; Object Layer Attributes #2, Číslo_vrstvy: 2; Object Layer Attributes #2, Tloušťka_vrstvy: 0.005 m; Object Layer Attributes #2, Tloušťka: 0 m; Object Layer Attributes #2, Faktor: 1; Object Layer Attributes #2, Označení: I.P7, I.P9; Object Layer Attributes #2, Materiál: ELEKTROSTATICKÝ VINYL; Object Layer Attributes #2, Vztažná_výška: 0; Object Layer Attributes #2, Delta_výšky: 0; Object Layer Attributes #2, Podlaží: 1.NP; Object Layer Attributes #2, Číslo místnosti: 1.03; Object Layer Attributes #2, Plošná únosnost: 5; Object Layer Attributes #2, Allright_Stavebni_dil_ID: 1469Ppl0000002403/02; Object Layer Attributes #2, Jednotka: m3; Object Layer Attributes #2, Název_objektu: Plocha podlahy; Object Layer Attributes #1, Označení: I.P7
 | 1.03 | SKIRTINGBOARD | FABION |  |  |  |  |  |  |  | NEW | NEMSOK - Kód prvku: PD00.03.0000; Práce: Povlakové podlahy; Faktor: 1; Materiál: FABION; Vztažná_výška: 0; Delta_výšky: 0; Allright_Stavebni_dil_ID: 1469Liš0000002868; Jednotka: m; Název_objektu: Lišta
 | 1.03 | CEILING | RASTR 1 0.03 m | 1 | 0.03 | 0 | 1 | 1469Dpl0000002407/01 | m3 | Plocha stropu | NEW | 12.737 | 0.03 | 0 | NEMSOK - Object Layer Attributes #1, Kód prvku: PH03.03.1001; Object Layer Attributes #1, Práce: Suché stavební práce; Object Layer Attributes #1, Materiál: RASTR 1; Object Layer Attributes #1, Výška svěšení: 0.6 m; Object Layer Attributes #1, Únosnost bodová: 0.5 kg; Pset_CoveringCommon - Flammability: bez požadavku
I.P7 | 1.08 | FLOORING | layer 0.295 m, ELEKTROSTATICKÝ VINYL 0.005 m | 1 | 0.295 | 0 | 1 | 1469Ppl0000002449/01 | m3 | Plocha podlahy | NEW | 74.804 | 0.3 | 0 | NEMSOK - Object Layer Attributes #2, Status: Nový; Object Layer Attributes #2, Kód prvku: PD06.03.1001; Object Layer Attributes #2, Práce: Povlakové podlahy; Object Layer Attributes #2, Číslo_vrstvy: 2; Object Layer Attributes #2, Tloušťka_vrstvy: 0.005 m; Object Layer Attributes #2, Tloušťka: 0 m; Object Layer Attributes #2, Faktor: 1; Object Layer Attributes #2, Označení: I.P7, I.P9; Object Layer Attributes #2, Materiál: ELEKTROSTATICKÝ VINYL; Object Layer Attributes #2, Vztažná_výška: 0; Object Layer Attributes #2, Delta_výšky: 0; Object Layer Attributes #2, Podlaží: 1.NP; Object Layer Attributes #2, Číslo místnosti: 1.08; Object Layer Attributes #2, Plošná únosnost: 5; Object Layer Attributes #2, Allright_Stavebni_dil_ID: 1469Ppl0000002449/02; Object Layer Attributes #2, Jednotka: m3; Object Layer Attributes #2, Název_objektu: Plocha podlahy; Object Layer Attributes #1, Označení: I.P7
 | 1.08 | SKIRTINGBOARD | FABION |  |  |  |  |  |  |  | NEW | NEMSOK - Kód prvku: PD00.03.0000; Práce: Povlakové podlahy; Faktor: 1; Materiál: FABION; Vztažná_výška: 0; Delta_výšky: 0; Allright_Stavebni_dil_ID: 1469Liš0000002874; Jednotka: m; Název_objektu: Lišta
 | 1.08 | CEILING | RASTR 3 0.03 m | 1 | 0.03 | 0 | 1 | 1469Dpl0000002451/01 | m3 | Plocha stropu | NEW | 74.804 | 0.03 | 0 | NEMSOK - Object Layer Attributes #1, Kód prvku: PH03.03.3001; Object Layer Attributes #1, Práce: Suché stavební práce; Object Layer Attributes #1, Materiál: RASTR 3; Object Layer Attributes #1, Výška svěšení: 0.6 m; Object Layer Attributes #1, Únosnost bodová: 0.5 kg; Pset_CoveringCommon - Flammability: bez požadavku
I.P9 | 1.13 | FLOORING | layer 0.145 m, ELEKTROSTATICKÝ VINYL 0.005 m | 1 | 0.145 | 0 | 1 | 1469Ppl0000002572/01 | m3 | Plocha podlahy | NEW | 1.825 | 0.15 | 0 | NEMSOK - Object Layer Attributes #2, Status: Nový; Object Layer Attributes #2, Kód prvku: PD06.03.1001; Object Layer Attributes #2, Práce: Povlakové podlahy; Object Layer Attributes #2, Číslo_vrstvy: 2; Object Layer Attributes #2, Tloušťka_vrstvy: 0.005 m; Object Layer Attributes #2, Tloušťka: 0 m; Object Layer Attributes #2, Faktor: 1; Object Layer Attributes #2, Označení: I.P7, I.P9; Object Layer Attributes #2, Materiál: ELEKTROSTATICKÝ VINYL; Object Layer Attributes #2, Vztažná_výška: 0; Object Layer Attributes #2, Delta_výšky: 0; Object Layer Attributes #2, Podlaží: 1.NP; Object Layer Attributes #2, Číslo místnosti: 1.13; Object Layer Attributes #2, Plošná únosnost: 3; Object Layer Attributes #2, Allright_Stavebni_dil_ID: 1469Ppl0000002572/02; Object Layer Attributes #2, Jednotka: m3; Object Layer Attributes #2, Název_objektu: Plocha podlahy; Object Layer Attributes #1, Označení: I.P9; Object Layer Attributes #2, Kročejová neprůzvučnost: 54.5
 | 1.13 | SKIRTINGBOARD | FABION |  |  |  |  |  |  |  | NEW | NEMSOK - Kód prvku: PD00.03.0000; Práce: Povlakové podlahy; Faktor: 1; Materiál: FABION; Vztažná_výška: 0; Delta_výšky: 0; Allright_Stavebni_dil_ID: 1469Liš0000002879; Jednotka: m; Název_objektu: Lišta
 | 1.13 | CEILING | RASTR 3 0.03 m | 1 | 0.03 | 0 | 1 | 1469Dpl0000002574/01 | m3 | Plocha stropu | NEW | 1.825 | 0.03 | 0 | NEMSOK - Object Layer Attributes #1, Kód prvku: PH03.03.3001; Object Layer Attributes #1, Práce: Suché stavební práce; Object Layer Attributes #1, Materiál: RASTR 3; Object Layer Attributes #1, Výška svěšení: 0.6 m; Object Layer Attributes #1, Únosnost bodová: 0.5 kg; Pset_CoveringCommon - Flammability: bez požadavku
 | 1.26b | FLOORING | layer 0.085 m, KERAMICKÁ DLAŽBA 0.015 m | 1 | 0.085 | 0 | 1 | 1469Ppl0000003046/01 | m3 | Plocha podlahy | NEW | 1.73 | 0.1 | 0 | NEMSOK - Object Layer Attributes #2, Status: Nový; Object Layer Attributes #2, Kód prvku: PD01.03.0001; Object Layer Attributes #2, Práce: Obklady a dlažby; Object Layer Attributes #2, Číslo_vrstvy: 2; Object Layer Attributes #2, Tloušťka_vrstvy: 0.015 m; Object Layer Attributes #2, Tloušťka: 0 m; Object Layer Attributes #2, Faktor: 1; Object Layer Attributes #2, Označení: I.P12; Object Layer Attributes #2, Materiál: KERAMICKÁ DLAŽBA; Object Layer Attributes #2, Vztažná_výška: 0; Object Layer Attributes #2, Delta_výšky: 0; Object Layer Attributes #2, Podlaží: 1.NP; Object Layer Attributes #2, Číslo místnosti: 1.26b; Object Layer Attributes #2, Plošná únosnost: 3; Object Layer Attributes #2, Allright_Stavebni_dil_ID: 1469Ppl0000003046/02; Object Layer Attributes #2, Jednotka: m3; Object Layer Attributes #2, Název_objektu: Plocha podlahy; Object Layer Attributes #2, Kročejová neprůzvučnost: 42.5
 | 1.26b | CEILING | RASTR 4 0.03 m | 1 | 0.03 | 0 | 1 | 1469Dpl0000003048/01 | m3 | Plocha stropu | NEW | 1.73 | 0.03 | 0 | NEMSOK - Object Layer Attributes #1, Kód prvku: PH03.03.4001; Object Layer Attributes #1, Práce: Suché stavební práce; Object Layer Attributes #1, Materiál: RASTR 4; Object Layer Attributes #1, Výška svěšení: 0.65 m; Object Layer Attributes #1, Únosnost bodová: 0.5 kg; Pset_CoveringCommon - Flammability: bez požadavku
 | 1.32 | FLOORING | layer 0.095 m, ELEKTROSTATICKÝ VINYL 0.005 m | 1 | 0.095 | 0 | 1 | 1469Ppl0000003119/01 | m3 | Plocha podlahy | NEW | 6.673 | 0.1 | 0 | NEMSOK - Object Layer Attributes #2, Status: Nový; Object Layer Attributes #2, Kód prvku: PD06.03.1001; Object Layer Attributes #2, Práce: Povlakové podlahy; Object Layer Attributes #2, Číslo_vrstvy: 2; Object Layer Attributes #2, Tloušťka_vrstvy: 0.005 m; Object Layer Attributes #2, Tloušťka: 0 m; Object Layer Attributes #2, Faktor: 1; Object Layer Attributes #2, Označení: I.P11; Object Layer Attributes #2, Materiál: ELEKTROSTATICKÝ VINYL; Object Layer Attributes #2, Vztažná_výška: 0; Object Layer Attributes #2, Delta_výšky: 0; Object Layer Attributes #2, Podlaží: 1.NP; Object Layer Attributes #2, Číslo místnosti: 1.32; Object Layer Attributes #2, Plošná únosnost: 3; Object Layer Attributes #2, Allright_Stavebni_dil_ID: 1469Ppl0000003119/02; Object Layer Attributes #2, Jednotka: m3; Object Layer Attributes #2, Název_objektu: Plocha podlahy; Object Layer Attributes #2, Kročejová neprůzvučnost: 41
 | 1.32 | CEILING | SÁDROVÁ OMÍTKA 0.015 m, MALBA 0.005 m | 1 | 0.015 | 0 | 1 | 1469Dpl0000003118/01 | m3 | Plocha stropu | NEW | 6.673 | 0.02 | 0 | NEMSOK - Object Layer Attributes #1, Kód prvku: OM04.03.0001; Object Layer Attributes #1, Práce: Omítky a štuky; Object Layer Attributes #1, Materiál: SÁDROVÁ OMÍTKA; Object Layer Attributes #1, Způsob provedení: strojní; Object Layer Attributes #2, Status: Nový; Object Layer Attributes #2, Kód prvku: MB03.03.1001; Object Layer Attributes #2, Práce: Malby a nátěry; Object Layer Attributes #2, Číslo_vrstvy: 2; Object Layer Attributes #2, Tloušťka_vrstvy: 0.005 m; Object Layer Attributes #2, Tloušťka: 0 m; Object Layer Attributes #2, Faktor: 1; Object Layer Attributes #2, Materiál: MALBA; Object Layer Attributes #2, Vztažná_výška: 0; Object Layer Attributes #2, Delta_výšky: 0; Object Layer Attributes #2, Podlaží: 1.NP; Object Layer Attributes #2, Allright_Stavebni_dil_ID: 1469Dpl0000003118/02; Object Layer Attributes #2, Jednotka: m3; Object Layer Attributes #2, Název_objektu: Plocha stropu; Object Layer Attributes #2, Způsob provedení: ruční
 | 1.32 | SKIRTINGBOARD | SOKLOVÁ PVC LIŠTA |  |  |  |  |  |  |  | NEW | NEMSOK - Kód prvku: PD00.03.0000; Práce: Povlakové podlahy; Faktor: 1; Materiál: SOKLOVÁ PVC LIŠTA; Vztažná_výška: 0; Delta_výšky: 0; Allright_Stavebni_dil_ID: 1469Liš0000003120; Jednotka: m; Název_objektu: Lišta; Plošná únosnost: 3

# IfcDoor: D101 (144)
Type - PredefinedType: DOOR; ParameterTakesPrecedence: no
NEMSOK - Jednotková_cena: 0; V6: 0 m; V7: 0 m; V8: 0 m; V9: 0; Verze programu: 2.2; Označení: D101; Plugin_Bezeichnung: MainObject; Plugin_Objektname: SmartPartCompressed; Uvažované procento prosklení: 100; Verze: 4.0; Dveře_Světlá-šířka: 0 m; Dveře_Světlá-výška: 0 m; Zárubeň/Rám_Materiál: Ocelová; Zárubeň/Rám_Povrch: EH; Specifikace: Interiérové dveře jednokřídlé plné; Jednotka: Kus; Název_objektu: Dveře - objekt+SmartPart; GlassSurface: 0; HeightWindowSillOutside: 0; HeightWindowSillInside: 0; OffsetOpeningBottom: 0; OffsetOpeningTop: 0; OffsetOpeningLeft: 0; OffsetOpeningRight: 0; DeductionOpeningBottom: 0
Pset_DoorCommon - IsExternal: no; ThermalTransmittance: 0 W/K/m2; HandicapAccessible: no; SmokeStop: no; SelfClosing: no; FireExit: no
Qto_DoorBaseQuantities - Perimeter: 0 m
Name | In | OverallHeight (m) = Height (m) | OverallWidth (m) = Width (m) | Koordinátor zavírání dveří | Name | Profile | Grade | Finish | Allright_Stavebni_dil_ID | DeductionOpeningLeft = DeductionOpeningRight | DeductionOpeningTop | Area (m2)
D101 | Půdorys 1.NP | 2.02 | 1.2 | yes | 1970 | 900 | 2135 | 100 | 1402Obj0798452138 | 50 | 50 | 2.424
D101 | Půdorys 1.NP | 2.02 | 0.7 | yes | 1970 | 900 | 2135 | 100 | 1402Obj0798453836 | 50 | 50 | 1.414
D101 | Půdorys 1.NP | 2.02 | 0.7 | yes | 1970 | 900 | 2135 | 100 | 1402Obj0798454027 | 50 | 50 | 1.414
D101 | Půdorys 1.NP | 2.02 | 0.7 | yes | 1970 | 900 | 2135 | 100 | 1402Obj0798454194 | 50 | 50 | 1.414
D101 | Půdorys 1.NP | 2.02 | 0.9 | yes | 1970 | 900 | 2135 | 100 | 1402Obj0798455062 | 50 | 50 | 1.818
D101 | Půdorys 1.NP | 2.02 | 0.9 | yes | 1970 | 900 | 2135 | 100 | 1402Obj0798454988 | 50 | 50 | 1.818
D101 | Půdorys 1.NP | 2.02 | 0.7 | yes | 1970 | 900 | 2135 | 100 | 1402Obj0798453968 | 50 | 50 | 1.414
D101 | Půdorys 1.NP | 2.02 | 0.9 | yes | 1970 | 900 | 2135 | 100 | 1402Obj0798455165 | 50 | 50 | 1.818
D101 | Půdorys 1.NP | 2.02 | 0.9 | yes | 1970 | 900 | 2135 | 100 | 1402Obj0798454078 | 50 | 50 | 1.818
D101 | Půdorys 1.NP | 2.02 | 0.9 | yes | 1970 | 900 | 2135 | 100 | 1402Obj0798455237 | 50 | 50 | 1.818
D101 | Půdorys 1.NP | 2.02 | 0.7 | yes | 1970 | 900 | 2135 | 100 | 1402Obj0798455215 | 50 | 50 | 1.414
D101 | Půdorys 1.NP | 2.02 | 0.8 | yes | 1970 | 900 | 2135 | 100 | 1402Obj0798457813 | 50 | 50 | 1.616
D101 | Půdorys 1.NP | 2.02 | 1 | yes | 1970 | 900 | 2135 | 100 | 1402Obj0798457479 | 50 | 50 | 2.02
D101 | Půdorys 1.NP | 2.02 | 0.8 | yes | 1970 | 900 | 2135 | 100 | 1402Obj0798457646 | 50 | 50 | 1.616
D101 | Půdorys 1.NP | 2.02 | 1.2 | yes | 1970 | 900 | 2135 | 100 | 1402Obj0798457934 | 50 | 50 | 2.424
D101 | Půdorys 1.NP | 2.02 | 1.2 | yes | 1970 | 900 | 2135 | 100 | 1402Obj0798463487 | 50 | 50 | 2.424
D101 | Půdorys 1.NP | 2.02 | 1 | yes | 1970 | 900 | 2135 | 100 | 1402Obj0798463509 | 50 | 50 | 2.02
D101 | Půdorys 1.NP | 2.02 | 0.8 | yes | 1970 | 900 | 2135 | 100 | 1402Obj0798459101 | 50 | 50 | 1.616
D101 | Půdorys 1.NP | 2.02 | 0.8 | yes | 1970 | 900 | 2135 | 100 | 1402Obj0798459018 | 50 | 50 | 1.616
D101 | Půdorys 1.NP | 2.02 | 1.2 | yes | 1970 | 900 | 2135 | 100 | 1402Obj0798456751 | 50 | 50 | 2.424
D101 | Půdorys 1.NP | 2.02 | 1.2 | yes | 1970 | 900 | 2135 | 100 | 1402Obj0798456788 | 50 | 50 | 2.424
D101 | Půdorys 1.NP | 2.02 | 0.9 | yes | 1970 | 900 | 2135 | 100 | 1402Obj0798463292 | 50 | 50 | 1.818
D101 | Půdorys 1.NP | 2.02 | 0.9 | yes | 1970 | 900 | 2135 | 100 | 1402Obj0798463329 | 50 | 50 | 1.818
D101 | Půdorys 1.NP | 2.02 | 1 | yes | 1970 | 900 | 2135 | 100 | 1402Obj0798463620 | 50 | 50 | 2.02
D101 | Půdorys 1.NP | 2.02 | 0.9 | yes | 1970 | 900 | 2135 | 100 | 1402Obj0798463735 | 50 | 50 | 1.818
D101 | Půdorys 1.NP | 2.02 | 0.7 | yes | 1970 | 900 | 2135 | 100 | 1402Obj0798463693 | 50 | 50 | 1.414
D101 | Půdorys 1.NP | 2.02 | 0.7 | yes | 1970 | 900 | 2135 | 100 | 1402Obj0798463690 | 50 | 50 | 1.414
D101 | Půdorys 1.NP | 2.02 | 0.9 | yes | 1970 | 900 | 2135 | 100 | 1402Obj0798464129 | 50 | 50 | 1.818
D101 | Půdorys 1.NP | 2.02 | 0.7 | yes | 1970 | 900 | 2135 | 100 | 1402Obj0798463805 | 50 | 50 | 1.414
D101 | Půdorys 1.NP | 2.02 | 0.9 | yes | 1970 | 900 | 2135 | 100 | 1402Obj0798463808 | 50 | 50 | 1.818
D101 | Půdorys 1.NP | 2.02 | 0.7 | yes | 1970 | 900 | 2135 | 100 | 1402Obj0798463811 | 50 | 50 | 1.414
D101 | Půdorys 1.NP | 2.02 | 0.7 | yes | 1970 | 900 | 2135 | 100 | 1402Obj0798463802 | 50 | 50 | 1.414
D101 | Půdorys 1.NP | 2.02 | 0.7 | yes | 1970 | 900 | 2135 | 100 | 1402Obj0798463799 | 50 | 50 | 1.414
D101 | Půdorys 1.NP | 2.02 | 0.7 | yes | 1970 | 900 | 2135 | 100 | 1402Obj0798464023 | 50 | 50 | 1.414
D101 | Půdorys 1.NP | 2.02 | 0.9 | yes | 1970 | 900 | 2135 | 100 | 1402Obj0798455098 | 50 | 50 | 1.818
D101 | Půdorys 1.PP | 2.02 | 0.9 | yes | 1970 | 900 | 2135 | 100 | 1352Obj0798437753 | 50 | 50 | 1.818
D101 | Půdorys 1.PP | 2.02 | 1.2 | yes | 1970 | 900 | 2135 | 100 | 1352Obj0798459532 | 50 | 50 | 2.424
D101 | Půdorys 1.PP | 2.02 | 0.7 | yes | 1970 | 900 | 2135 | 100 | 1352Obj0798460315 | 50 | 50 | 1.414
D101 | Půdorys 1.PP | 2.02 | 0.7 | yes | 1970 | 900 | 2135 | 100 | 1352Obj0798471325 | 50 | 50 | 1.414
D101 | Půdorys 1.PP | 2.02 | 1.2 | yes | 1970 | 900 | 2135 | 100 | 1352Obj0798471690 | 50 | 50 | 2.424
D101 | Půdorys 1.PP | 2.02 | 0.7 | yes | 1970 | 900 | 2135 | 100 | 1352Obj0798460425 | 50 | 50 | 1.414
D101 | Půdorys 1.PP | 2.02 | 0.7 | yes | 1970 | 900 | 2135 | 100 | 1352Obj0798460370 | 50 | 50 | 1.414
D101 | Půdorys 1.PP | 2.02 | 1.2 | yes | 1970 | 900 | 2135 | 100 | 1352Obj0798460145 | 50 | 50 | 2.424
D101 | Půdorys 1.PP | 2.02 | 0.7 | yes | 1970 | 900 | 2135 | 100 | 1352Obj0798473359 | 50 | 50 | 1.414
D101 | Půdorys 1.PP | 2.02 | 1.2 | yes | 1970 | 900 | 2135 | 100 | 1352Obj0798473194 | 50 | 50 | 2.424
D101 | Půdorys 1.PP | 2.02 | 0.9 | yes | 1970 | 900 | 2135 | 100 | 1352Obj0798473148 | 50 | 50 | 1.818
D101 | Půdorys 1.PP | 2.02 | 0.7 | yes | 1970 | 900 | 2135 | 100 | 1352Obj0798471371 | 50 | 50 | 1.414
D101 | Půdorys 1.PP | 2.02 | 0.9 | yes | 1970 | 900 | 2135 | 100 | 1352Obj0798473022 | 50 | 50 | 1.818
D101 | Půdorys 1.PP | 2.02 | 0.9 | yes | 1970 | 900 | 2135 | 100 | 1352Obj0798473068 | 50 | 50 | 1.818
D101 | Půdorys 1.PP | 2.02 | 1.2 | yes | 1970 | 900 | 2135 | 100 | 1352Obj0798471536 | 50 | 50 | 2.424
D101 | Půdorys 1.PP | 2.02 | 1.2 | yes | 1970 | 900 | 2135 | 100 | 1352Obj0798497669 | 50 | 50 | 2.424
D101 | Půdorys 1.PP | 2.02 | 1.03 | yes | 1970 | 900 | 2135 | 100 | 1352Obj0798460987 | 50 | 50 | 2.081
D101 | Půdorys 1.PP | 2.02 | 0.7 | yes | 1970 | 900 | 2135 | 100 | 1352Obj0798496985 | 50 | 50 | 1.414
D101 | Půdorys 1.PP | 2.02 | 0.7 | yes | 1970 | 900 | 2135 | 100 | 1352Obj0798497350 | 50 | 50 | 1.414
D101 | Půdorys 1.PP | 2.02 | 0.9 | yes | 1970 | 900 | 2135 | 100 | 1352Obj0798497442 | 50 | 50 | 1.818
D101 | Půdorys 1.PP | 2.02 | 1.2 | yes | 1970 | 900 | 2135 | 100 | 1352Obj0798500115 | 50 | 50 | 2.424
D101 | Půdorys 1.PP | 2.02 | 1.2 | yes | 1970 | 900 | 2135 | 100 | 1352Obj0798472129 | 50 | 50 | 2.424
D101 | Půdorys 1.PP | 2.02 | 0.9 | yes | 1970 | 900 | 2135 | 100 | 1352Obj0798472594 | 50 | 50 | 1.818
D101 | Půdorys 1.NP | 2.02 | 1.2 | yes | 1970 | 900 | 2135 | 100 | 1452Obj1096117187 | 50 | 50 | 2.424
D101 | Půdorys 1.NP | 2.02 | 1.2 | yes | 1970 | 900 | 2135 | 100 | 1452Obj0798446365 | 50 | 50 | 2.424
D101 | Půdorys 1.NP | 2.02 | 1.2 | yes | 1970 | 900 | 2135 | 100 | 1452Obj0798446448 | 50 | 50 | 2.424
D101 | Půdorys 1.NP | 2.02 | 1.2 | yes | 1970 | 900 | 2135 | 100 | 1452Obj1096101440 | 50 | 50 | 2.424
D101 | Půdorys 1.NP | 2.02 | 1.2 | yes | 1970 | 900 | 2135 | 100 | 1452Obj1096101527 | 50 | 50 | 2.424
D101 | Půdorys 1.NP | 2.02 | 1 | yes | 1970 | 900 | 2135 | 100 | 1452Obj1096101558 | 50 | 50 | 2.02
D101 | Půdorys 1.NP | 2.02 | 0.9 | yes | 1970 | 900 | 2135 | 100 | 1452Obj0798447885 | 50 | 50 | 1.818
D101 | Půdorys 1.NP | 2.02 | 0.8 | yes | 1970 | 900 | 2135 | 100 | 1452Obj0798448131 | 50 | 50 | 1.616
D101 | Půdorys 1.NP | 2.02 | 0.8 | yes | 1970 | 900 | 2135 | 100 | 1452Obj0798448059 | 50 | 50 | 1.616
D101 | Půdorys 1.NP | 2.02 | 0.9 | yes | 1970 | 900 | 2135 | 100 | 1452Obj0798447357 | 50 | 50 | 1.818
D101 | Půdorys 1.NP | 2.02 | 0.9 | yes | 1970 | 900 | 2135 | 100 | 1452Obj0798447438 | 50 | 50 | 1.818
D101 | Půdorys 1.NP | 2 | 0.76 | yes | 1970 | 900 | 2135 | 100 | 1452Obj1096101344 | 30 | 30 | 1.52
D101 | Půdorys 1.NP | 2 | 0.76 | yes | 1970 | 900 | 2135 | 100 | 1452Obj1096101354 | 30 | 30 | 1.52
D101 | Půdorys 1.NP | 2 | 0.76 | yes | 1970 | 900 | 2135 | 100 | 1452Obj1096101304 | 30 | 30 | 1.52
D101 | Půdorys 1.NP | 2.02 | 1 | yes | 1970 | 900 | 2135 | 100 | 1452Obj1096104643 | 50 | 50 | 2.02
D101 | Půdorys 1.NP | 2.02 | 1 | yes | 1970 | 900 | 2135 | 100 | 1452Obj1096102786 | 50 | 50 | 2.02
D101 | Půdorys 1.NP | 2.02 | 1 | yes | 1970 | 900 | 2135 | 100 | 1452Obj1096103473 | 50 | 50 | 2.02
D101 | Půdorys 1.NP | 2.02 | 1 | yes | 1970 | 900 | 2135 | 100 | 1452Obj1096104086 | 50 | 50 | 2.02
D101 | Půdorys 1.NP | 2.02 | 1 | yes | 1970 | 900 | 2135 | 100 | 1452Obj1096104215 | 50 | 50 | 2.02 | Pset_DoorCommon - FireRating: EW 30DP3 - C
D101 | Půdorys 1.NP | 2.02 | 1 | yes | 1970 | 900 | 2135 | 100 | 1452Obj1096112953 | 50 | 50 | 2.02
D101 | Půdorys 1.NP | 2.02 | 1 | yes | 1970 | 900 | 2135 | 100 | 1452Obj1096113072 | 50 | 50 | 2.02
D101 | Půdorys 1.NP | 2.02 | 0.8 | yes | 1970 | 900 | 2135 | 100 | 1452Obj1096118359 | 50 | 50 | 1.616
D101 | Půdorys 1.NP | 2.02 | 0.7 | yes | 1970 | 900 | 2135 | 100 | 1452Obj1096110596 | 50 | 50 | 1.414
D101 | Půdorys 1.NP | 2.02 | 0.7 | yes | 1970 | 900 | 2135 | 100 | 1452Obj1096110670 | 50 | 50 | 1.414
D101 | Půdorys 1.NP | 2.02 | 1.2 | yes | 1970 | 900 | 2135 | 100 | 1452Obj1096113396 | 50 | 50 | 2.424
D101 | Půdorys 1.NP | 2.02 | 1.2 | yes | 1970 | 900 | 2135 | 100 | 1452Obj1096113442 | 50 | 50 | 2.424
D101 | Půdorys 1.NP | 2.02 | 1.2 | yes | 1970 | 900 | 2135 | 100 | 1452Obj1096116332 | 50 | 50 | 2.424
D101 | Půdorys 1.NP | 2.02 | 0.8 | yes | 1970 | 900 | 2135 | 100 | 1452Obj1096113782 | 50 | 50 | 1.616
D101 | Půdorys 1.NP | 2.02 | 0.8 | yes | 1970 | 900 | 2135 | 100 | 1452Obj1096113701 | 50 | 50 | 1.616
D101 | Půdorys 1.NP | 2.02 | 0.8 | yes | 1970 | 900 | 2135 | 100 | 1452Obj1096114096 | 50 | 50 | 1.616
D101 | Půdorys 1.NP | 2.02 | 0.8 | yes | 1970 | 900 | 2135 | 100 | 1452Obj1096114153 | 50 | 50 | 1.616
D101 | Půdorys 1.NP | 2.02 | 0.8 | yes | 1970 | 900 | 2135 | 100 | 1452Obj0798433048 | 50 | 50 | 1.616
D101 | Půdorys 1.NP | 2.02 | 0.9 | yes | 1970 | 900 | 2135 | 100 | 1452Obj0798433122 | 50 | 50 | 1.818
D101 | Půdorys 1.NP | 2.02 | 0.8 | yes | 1970 | 900 | 2135 | 100 | 1452Obj1096114234 | 50 | 50 | 1.616
D101 | Půdorys 1.NP | 2.02 | 0.8 | yes | 1970 | 900 | 2135 | 100 | 1452Obj1096114292 | 50 | 50 | 1.616
D101 | Půdorys 1.NP | 2.02 | 0.8 | yes | 1970 | 900 | 2135 | 100 | 1452Obj1096115261 | 50 | 50 | 1.616
D101 | Půdorys 1.NP | 2.02 | 1 | yes | 1970 | 900 | 2135 | 100 | 1452Obj0798433510 | 50 | 50 | 2.02
D101 | Půdorys 1.NP | 2.02 | 1.2 | yes | 1970 | 900 | 2135 | 100 | 1452Obj1096116310 | 50 | 50 | 2.424
D101 | Půdorys 1.NP | 2.02 | 1.2 | yes | 1970 | 900 | 2135 | 100 | 1452Obj1096116288 | 50 | 50 | 2.424
D101 | Půdorys 1.NP | 2.02 | 0.8 | yes | 1970 | 900 | 2135 | 100 | 1452Obj1096117426 | 50 | 50 | 1.616
D101 | Půdorys 1.NP | 2.02 | 0.8 | yes | 1970 | 900 | 2135 | 100 | 1452Obj1096117500 | 50 | 50 | 1.616
D101 | Půdorys 1.NP | 2.02 | 1.2 | yes | 1970 | 900 | 2135 | 100 | 1452Obj1096104150 | 50 | 50 | 2.424
D101 | Půdorys 1.NP | 2.02 | 1.2 | yes | 1970 | 900 | 2135 | 100 | 1452Obj1096103584 | 50 | 50 | 2.424
D101 | Půdorys 1.NP | 2.02 | 1.2 | yes | 1970 | 900 | 2135 | 100 | 1452Obj1096102457 | 50 | 50 | 2.424
D101 | Půdorys 1.NP | 2.02 | 1.2 | yes | 1970 | 900 | 2135 | 100 | 1452Obj1096102411 | 50 | 50 | 2.424
D101 | Půdorys 1.NP | 2.02 | 0.8 | yes | 1970 | 900 | 2135 | 100 | 1452Obj1096101814 | 50 | 50 | 1.616
D101 | Půdorys 1.NP | 2.02 | 1.2 | yes | 1970 | 900 | 2135 | 100 | 1452Obj1096102206 | 50 | 50 | 2.424
D101 | Půdorys 1.NP | 2.02 | 1.2 | yes | 1970 | 900 | 2135 | 100 | 1452Obj1096103051 | 50 | 50 | 2.424
D101 | Půdorys 1.NP | 2.02 | 0.8 | yes | 1970 | 900 | 2135 | 100 | 1452Obj1096103132 | 50 | 50 | 1.616
D101 | Půdorys 1.NP | 2.02 | 1.2 | yes | 1970 | 900 | 2135 | 100 | 1452Obj1096103239 | 50 | 50 | 2.424
D101 | Půdorys 1.NP | 2.02 | 1.2 | yes | 1970 | 900 | 2135 | 100 | 1452Obj1096117802 | 50 | 50 | 2.424
D101 | Půdorys 1.NP | 2.02 | 0.8 | yes | 1970 | 900 | 2135 | 100 | 1452Obj1096118418 | 50 | 50 | 1.616
D101 | Půdorys 1.NP | 2.02 | 0.8 | yes | 1970 | 900 | 2135 | 100 | 1452Obj1096118469 | 50 | 50 | 1.616
D101 | Půdorys 1.NP | 2.02 | 0.8 | yes | 1970 | 900 | 2135 | 100 | 1452Obj1096118328 | 50 | 50 | 1.616
D101 | Půdorys 1.NP | 2.02 | 1 | yes | 1970 | 900 | 2135 | 100 | 1452Obj1096112803 | 50 | 50 | 2.02
D101 | Půdorys 1.NP | 2.02 | 0.8 | yes | 1970 | 900 | 2135 | 100 | 1452Obj1096118280 | 50 | 50 | 1.616
D101 | Půdorys 1.NP | 2.02 | 0.8 | yes | 1970 | 900 | 2135 | 100 | 1452Obj1096118568 | 50 | 50 | 1.616
D101 | Půdorys 1.NP | 2.18 | 1.2 | yes | 1970 | 900 | 2135 | 100 | 1452Obj0798424644 | 80 | 80 | 2.616
D101 | Půdorys 1.NP | 0.85 | 0.86 |  |  |  |  |  | 1464Obj1096144136 | 30 | 0 | 0.731 | NEMSOK - Kód prvku: TV00.03.2002; Číslo místnosti: K1.08; Podlaží: 1.NP; Kování_Zámek: bez; Pset_DoorCommon - Status: NEW; SecurityRating: bez
D101 | Půdorys 2.NP | 2.02 | 1 | yes | 1970 | 900 | 2135 | 100 | 1552Obj0798441844 | 50 | 50 | 2.02
D101 | Půdorys 2.NP | 2.02 | 1 | yes | 1970 | 900 | 2135 | 100 | 1552Obj0798438762 | 50 | 50 | 2.02
D101 | Půdorys 2.NP | 2.02 | 1 | yes | 1970 | 900 | 2135 | 100 | 1552Obj0798443645 | 50 | 50 | 2.02
D101 | Půdorys 2.NP | 2.02 | 0.7 | yes | 1970 | 900 | 2135 | 100 | 1552Obj0798442951 | 50 | 50 | 1.414
D101 | Půdorys 2.NP | 2.02 | 0.7 | yes | 1970 | 900 | 2135 | 100 | 1552Obj0798442726 | 50 | 50 | 1.414
D101 | Půdorys 2.NP | 2.02 | 0.7 | yes | 1970 | 900 | 2135 | 100 | 1552Obj0798442870 | 50 | 50 | 1.414
D101 | Půdorys 2.NP | 2.02 | 0.7 | yes | 1970 | 900 | 2135 | 100 | 1552Obj0798442798 | 50 | 50 | 1.414
D101 | Půdorys 2.NP | 2.02 | 1 | yes | 1970 | 900 | 2135 | 100 | 1552Obj0798443457 | 50 | 50 | 2.02
D101 | Půdorys 2.NP | 2.02 | 0.7 | yes | 1970 | 900 | 2135 | 100 | 1552Obj0798453615 | 50 | 50 | 1.414
D101 | Půdorys 2.NP | 2.02 | 0.7 | yes | 1970 | 900 | 2135 | 100 | 1552Obj0798442333 | 50 | 50 | 1.414
D101 | Půdorys 2.NP | 2.02 | 0.7 | yes | 1970 | 900 | 2135 | 100 | 1552Obj0798442440 | 50 | 50 | 1.414
D101 | Půdorys 2.NP | 2.02 | 0.7 | yes | 1970 | 900 | 2135 | 100 | 1552Obj0798442547 | 50 | 50 | 1.414
D101 | Půdorys 2.NP | 2.02 | 0.7 | yes | 1970 | 900 | 2135 | 100 | 1552Obj0798442619 | 50 | 50 | 1.414
D101 | Půdorys 2.NP | 2.02 | 0.7 | yes | 1970 | 900 | 2135 | 100 | 1552Obj0798443023 | 50 | 50 | 1.414
D101 | Půdorys 2.NP | 2.02 | 1 | yes | 1970 | 900 | 2135 | 100 | 1552Obj0798444419 | 50 | 50 | 2.02
D101 | Půdorys 2.NP | 2.02 | 0.9 | yes | 1970 | 900 | 2135 | 100 | 1552Obj0798444456 | 50 | 50 | 1.818
D101 | Půdorys 2.NP | 2.02 | 0.9 | yes | 1970 | 900 | 2135 | 100 | 1552Obj0798444604 | 50 | 50 | 1.818
D101 | Půdorys 2.NP | 2.02 | 0.9 | yes | 1970 | 900 | 2135 | 100 | 1552Obj0798444863 | 50 | 50 | 1.818
D101 | Půdorys 2.NP | 2.02 | 1 | yes | 1970 | 900 | 2135 | 100 | 1552Obj0798453494 | 50 | 50 | 2.02
D101 | Půdorys 2.NP | 2.02 | 0.9 | yes | 1970 | 900 | 2135 | 100 | 1552Obj0798453696 | 50 | 50 | 1.818
D101 | Půdorys 3.NP | 2.02 | 1.2 | yes | 1970 | 900 | 2135 | 100 | 1652Obj0798439916 | 50 | 50 | 2.424
D101 | Půdorys 4.NP | 2.02 | 1 | yes | 1970 | 900 | 2135 | 100 | 1752Obj0798425987 | 50 | 50 | 2.02
D101 | Půdorys 4.NP | 2.02 | 0.9 | yes | 1970 | 900 | 2135 | 100 | 1752Obj0798427815 | 50 | 50 | 1.818
D101 | Půdorys 4.NP | 2.02 | 1.2 | yes | 1970 | 900 | 2135 | 100 | 1752Obj0798427884 | 50 | 50 | 2.424
D101 | Půdorys 5.NP | 2.02 | 0.9 | yes | 1970 | 900 | 2135 | 100 | 1852Obj0798426039 | 50 | 50 | 1.818
D101 | Půdorys 5.NP | 2 | 0.83 | yes | 1970 | 900 | 2135 | 100 | 1852Obj0798427812 | 20 | 20 | 1.66
D101 | Půdorys 6.NP | 2.02 | 0.9 | yes | 1970 | 900 | 2135 | 100 | 1952Obj0798427137 | 50 | 50 | 1.818

# IfcDoor: D401 (24)
Type - PredefinedType: DOOR; ParameterTakesPrecedence: no
NEMSOK - Jednotková_cena: 0; V6: 0 m; V7: 0 m; V8: 0 m; V9: 0; Verze programu: 2.2; Označení: D401; Plugin_Bezeichnung: MainObject; Plugin_Objektname: SmartPartCompressed; Uvažované procento prosklení: 100; Verze: 4.0; Koordinátor zavírání dveří: yes; Name: 1970; Profile: 1550; Grade: 2135; Finish: 100; Dveře_Světlá-šířka: 0 m; Dveře_Světlá-výška: 0 m; Zárubeň/Rám_Materiál: Ocelová; Zárubeň/Rám_Povrch: EH; Specifikace: Interiérové dveře dvoukřídlé plné; Jednotka: Kus; Název_objektu: Dveře - objekt+SmartPart; HeightWindowSillOutside: 0; HeightWindowSillInside: 0; OffsetOpeningBottom: 0; OffsetOpeningTop: 0; OffsetOpeningLeft: 0; OffsetOpeningRight: 0
Pset_DoorCommon - IsExternal: no; ThermalTransmittance: 0 W/K/m2; HandicapAccessible: no; SmokeStop: no; SelfClosing: no; FireExit: no
Qto_DoorBaseQuantities - Perimeter: 0 m
Name | In | OverallHeight (m) | OverallWidth (m) | Allright_Stavebni_dil_ID | GlassSurface | DeductionOpeningBottom | DeductionOpeningLeft = DeductionOpeningRight | DeductionOpeningTop | Height (m) | Width (m) | Area (m2)
D401 | Půdorys 1.PP | 2.02 | 1.8 | 1302Obj0798449453 | 0 | 0 | 50 | 50 | 2.02 | 1.8 | 3.636
D401 | Půdorys 1.PP | 2.02 | 0.9 | 1302Obj0798455757 | 0 | 0 | 50 | 50 | 2.02 | 0.9 | 1.818
D401 | Půdorys 1.PP | 2.02 | 0.9 | 1302Obj0798455639 | 0 | 0 | 50 | 50 | 2.02 | 0.9 | 1.818
D401 | Půdorys 1.PP | 2.02 | 1.6 | 1302Obj0798455612 | 0 | 0 | 50 | 50 | 2.02 | 1.6 | 3.232
D401 | Půdorys 1.PP | 2.02 | 1.6 | 1302Obj0798455500 | 0 | 0 | 50 | 50 | 2.02 | 1.6 | 3.232
D401 | Půdorys 1.PP | 2.02 | 0.9 | 1302Obj0798455735 | 0 | 0 | 50 | 50 | 2.02 | 0.9 | 1.818
D401 | Půdorys 1.PP | 2.02 | 1.7 | 1302Obj0798455430 | 0 | 0 | 50 | 50 | 2.02 | 1.7 | 3.434
D401 | Půdorys 1.PP | 2.02 | 0.9 | 1302Obj0798455779 | 0 | 0 | 50 | 50 | 2.02 | 0.9 | 1.818
D401 | Půdorys 1.PP | 2.02 | 1.7 | 1302Obj0798455263 | 0 | 0 | 50 | 50 | 2.02 | 1.7 | 3.434
D401 | Půdorys 1.PP | 2.02 | 0.9 | 1302Obj0798455939 | 0 | 0 | 50 | 50 | 2.02 | 0.9 | 1.818
D401 | Půdorys 1.PP | 2.02 | 0.9 | 1302Obj0798455801 | 0 | 0 | 50 | 50 | 2.02 | 0.9 | 1.818
D401 | Půdorys 1.NP | 2.14 | 1.84 | 1402Obj0798449486 | 2.5821 | 0 | 20 | 20 | 2.12 | 1.8 | 3.816 | Pset_DoorCommon - FireRating: EW 30DP3 - C+S; SecurityRating: SA
D401 | Půdorys 1.NP | 2.24 | 1.68 | 1402Obj0798453371 | 2.398 | 0 | 20 | 20 | 2.22 | 1.64 | 3.641 | Pset_DoorCommon - FireRating: EW 30DP3 - C+S; SecurityRating: SA
D401 | Půdorys 1.NP | 2.24 | 1.68 | 1402Obj0798456863 | 2.398 | 0 | 20 | 20 | 2.22 | 1.64 | 3.641 | Pset_DoorCommon - FireRating: EW 30DP3 - C+S; SecurityRating: SA
D401 | Půdorys 1.NP | 2.24 | 1.63 | 1402Obj0798458225 | 2.7 | 0 | 20 | 20 | 2.22 | 1.59 | 3.53 | Pset_DoorCommon - FireRating: EW 30DP3 - C+S; SecurityRating: SA
D401 | Půdorys 1.NP | 2.14 | 1.53 | 1402Obj0798458512 | 2.375 | 0 | 20 | 20 | 2.12 | 1.49 | 3.159 | Pset_DoorCommon - FireRating: EW 30DP3 - C+S; SecurityRating: SA
D401 | Půdorys 1.NP | 2.14 | 1.53 | 1402Obj0798458609 | 2.375 | 0 | 20 | 20 | 2.12 | 1.49 | 3.159 | Pset_DoorCommon - FireRating: EW 30DP3 - C+S; SecurityRating: SA
D401 | Půdorys 1.NP | 2.2 | 2.35 | 1402Obj0798459249 | 3.52305 | 0 | 475 | 0 | 2.2 | 2.35 | 5.17 | Pset_DoorCommon - FireRating: EW 30DP3 - C+S; SecurityRating: SA
D401 | Půdorys 1.PP | 2.12 | 1.55 | 1352Obj0798470480 | 0.15345 | 100 | 50 | 50 | 2.12 | 1.55 | 3.286 | Pset_DoorCommon - Status: DEMOLISH
D401 | Půdorys 1.PP | 2.02 | 1.55 | 1352Obj0798471746 | 0 | 0 | 50 | 50 | 2.02 | 1.55 | 3.131
D401 | Půdorys 1.PP | 2.02 | 1.55 | 1352Obj0798470850 | 0 | 0 | 50 | 50 | 2.02 | 1.55 | 3.131
D401 | Půdorys 1.PP | 2.02 | 1.55 | 1352Obj0798449400 | 0 | 0 | 50 | 50 | 2.02 | 1.55 | 3.131
D401 | Půdorys 1.NP | 2.1 | 1.8 | 1452Obj1096101960 | 0 | 0 | 75 | 75 | 2.1 | 1.8 | 3.78
D401 | Půdorys 1.NP | 2.2 | 3 | 1452Obj1096112319 | 4.35006 | 0 | 900 | 0 | 2.2 | 3 | 6.6 | Pset_DoorCommon - FireRating: EI 30DP3 - C+S; SecurityRating: SA

# IfcDoor: D501 (10)
Type - PredefinedType: DOOR; ParameterTakesPrecedence: no
OverallHeight: 2.02 m
NEMSOK - Jednotková_cena: 0; V6: 0 m; V7: 0 m; V8: 0 m; V9: 0; Verze programu: 2.2; Označení: D501; Plugin_Bezeichnung: MainObject; Plugin_Objektname: SmartPartCompressed; Uvažované procento prosklení: 100; Verze: 4.0; Koordinátor zavírání dveří: yes; Name: 1970; Profile: 1550; Grade: 2135; Finish: 100; Dveře_Světlá-šířka: 0 m; Dveře_Světlá-výška: 0 m; Zárubeň/Rám_Materiál: Ocelová; Zárubeň/Rám_Povrch: EH; Specifikace: Interiérové dveře dvoukřídlé plné; Jednotka: Kus; Název_objektu: Dveře - objekt+SmartPart; GlassSurface: 0; HeightWindowSillOutside: 0; HeightWindowSillInside: 0; OffsetOpeningBottom: 0; OffsetOpeningTop: 0; OffsetOpeningLeft: 0; OffsetOpeningRight: 0; DeductionOpeningBottom: 0; DeductionOpeningLeft: 50; DeductionOpeningRight: 50; DeductionOpeningTop: 50
Pset_DoorCommon - IsExternal: no; ThermalTransmittance: 0 W/K/m2; HandicapAccessible: no; SmokeStop: no; SelfClosing: no; FireExit: no
Qto_DoorBaseQuantities - Height: 2.02 m; Perimeter: 0 m
Name | In | OverallWidth (m) = Width (m) | Allright_Stavebni_dil_ID | Area (m2)
D501 | Půdorys 1.PP | 1.55 | 1352Obj0798427341 | 3.131
D501 | Půdorys 2.NP | 1.55 | 1552Obj0798428003 | 3.131
D501 | Půdorys 2.NP | 1.35 | 1552Obj0798437689 | 2.727
D501 | Půdorys 2.NP | 1.35 | 1552Obj0798438329 | 2.727
D501 | Půdorys 2.NP | 1.55 | 1552Obj0798444397 | 3.131
D501 | Půdorys 3.NP | 1.55 | 1652Obj0798428305 | 3.131
D501 | Půdorys 3.NP | 1.55 | 1652Obj0798437614 | 3.131
D501 | Půdorys 4.NP | 1.55 | 1752Obj0000009935 | 3.131
D501 | Půdorys 4.NP | 1.55 | 1752Obj0000019370 | 3.131
D501 | Půdorys 5.NP | 1.55 | 1852Obj0798427921 | 3.131

# IfcDoor: D701 (5)
Type - PredefinedType: DOOR; ParameterTakesPrecedence: no
OverallHeight: 2.75 m; OverallWidth: 0.9 m
NEMSOK - Jednotková_cena: 0; V6: 0 m; V7: 0 m; V8: 0 m; V9: 0; Verze programu: 2.2; Označení: D701; Plugin_Bezeichnung: MainObject; Plugin_Objektname: SmartPartCompressed; Uvažované procento prosklení: 100; Verze: 4.0; Koordinátor zavírání dveří: yes; Name: 1970; Profile: 1550; Grade: 2135; Finish: 100; Dveře_Světlá-šířka: 0 m; Dveře_Světlá-výška: 0 m; Zárubeň/Rám_Materiál: Ocelová; Zárubeň/Rám_Povrch: EH; Specifikace: Interiérové dveře jednokřídlé plné s horním proskleným světlíkem; Jednotka: Kus; Název_objektu: Dveře - objekt+SmartPart; GlassSurface: 1.4884; HeightWindowSillOutside: 0; HeightWindowSillInside: 0; OffsetOpeningBottom: 0; OffsetOpeningTop: 0; OffsetOpeningLeft: 0; OffsetOpeningRight: 0; DeductionOpeningBottom: 0; DeductionOpeningLeft: 60; DeductionOpeningRight: 60; DeductionOpeningTop: 650
Pset_DoorCommon - IsExternal: no; ThermalTransmittance: 0 W/K/m2; HandicapAccessible: no; SmokeStop: no; SelfClosing: no; FireExit: no
Qto_DoorBaseQuantities - Height: 2.75 m; Width: 0.9 m; Area: 2.475 m2; Perimeter: 0 m
Name | In | Allright_Stavebni_dil_ID
D701 | Půdorys 2.NP | 1552Obj0798428704
D701 | Půdorys 3.NP | 1652Obj0798431799
D701 | Půdorys 3.NP | 1652Obj0798431796
D701 | Půdorys 4.NP | 1752Obj0000010424
D701 | Půdorys 4.NP | 1752Obj0000010429

# IfcDoor: DF01 (2)
In: Půdorys 1.NP
Type - PredefinedType: DOOR; ParameterTakesPrecedence: no
NEMSOK - Jednotková_cena: 0; V6: 0 m; V7: 0 m; V8: 0 m; V9: 0; Verze programu: 2.2; Označení: DF01; Plugin_Bezeichnung: MainObject; Plugin_Objektname: SmartPartCompressed; Uvažované procento prosklení: 0; Verze: 4.0; Koordinátor zavírání dveří: yes; Name: 1970; Profile: 900; Grade: 2135; Finish: 100; Dveře_Světlá-šířka: 0 m; Dveře_Světlá-výška: 0 m; Specifikace: Vchodové dveře jednokřídlé plné; Jednotka: Kus; Název_objektu: Dveře - objekt+SmartPart; HeightWindowSillOutside: 0; HeightWindowSillInside: 0; OffsetOpeningBottom: 0; OffsetOpeningTop: 0; OffsetOpeningLeft: 0; OffsetOpeningRight: 0; DeductionOpeningBottom: 0; DeductionOpeningLeft: 80; DeductionOpeningRight: 80
Pset_DoorCommon - IsExternal: yes; ThermalTransmittance: 0.9 W/K/m2; HandicapAccessible: no; SmokeStop: no; SelfClosing: no; FireExit: no; SecurityRating: 2
Qto_DoorBaseQuantities - Perimeter: 0 m
Name | OverallHeight (m) = Height (m) | OverallWidth (m) = Width (m) | Allright_Stavebni_dil_ID | GlassSurface | DeductionOpeningTop | Area (m2)
DF01 | 3.1 | 1.2 | 1452Obj0798427077 | 0.8736 | 1000 | 3.72
DF01 | 2.75 | 1.9 | 1452Obj0798428120 | 0.8526 | 650 | 5.225

# IfcDoor: DH501
In: Půdorys 3.NP
Type - PredefinedType: DOOR; ParameterTakesPrecedence: no
OverallHeight: 2.2 m; OverallWidth: 1.65 m
NEMSOK - Jednotková_cena: 0; V6: 0 m; V7: 0 m; V8: 0 m; V9: 0; Verze programu: 2.2; Označení: DH501; Plugin_Bezeichnung: MainObject; Plugin_Objektname: SmartPartCompressed; Uvažované procento prosklení: 100; Verze: 4.0; Koordinátor zavírání dveří: yes; Name: 1970; Profile: 1550; Grade: 2135; Finish: 100; Dveře_Světlá-šířka: 0 m; Dveře_Světlá-výška: 0 m; Zárubeň/Rám_Materiál: Hliníková; Zárubeň/Rám_Povrch: EH; Specifikace: Interiérové dveře dvoukřídlé plné; Allright_Stavebni_dil_ID: 1652Obj0798444995; Jednotka: Kus; Název_objektu: Dveře - objekt+SmartPart; GlassSurface: 0; HeightWindowSillOutside: 0; HeightWindowSillInside: 0; OffsetOpeningBottom: 0; OffsetOpeningTop: 0; OffsetOpeningLeft: 0; OffsetOpeningRight: 0; DeductionOpeningBottom: 0; DeductionOpeningLeft: 75; DeductionOpeningRight: 75; DeductionOpeningTop: 75
Pset_DoorCommon - IsExternal: no; ThermalTransmittance: 0 W/K/m2; HandicapAccessible: no; SmokeStop: no; SelfClosing: no; FireExit: no
Qto_DoorBaseQuantities - Height: 2.2 m; Width: 1.65 m; Area: 3.63 m2; Perimeter: 0 m

# IfcDoor: I.D001
In: Půdorys 1.PP
Type - PredefinedType: DOOR; ParameterTakesPrecedence: no
OverallHeight: 2.12 m; OverallWidth: 1.55 m
NEMSOK - Kód prvku: DD01.02.0001; Jednotková_cena: 0; V6: 0 m; V7: 0 m; V8: 0 m; V9: 0; Verze programu: 2.2; Označení: I.D001; Plugin_Bezeichnung: MainObject; Plugin_Objektname: SmartPartCompressed; Uvažované procento prosklení: 100; Verze: 4.0; Podlaží: 1.PP; šířka: 1450; výška: 1970; Funkce (venkovní): Ne; Připojení EZS: Ne; Připojení NN: Ne; Připojení EPS: Ne; Připojení MaR: Ne; Připojení ACS: Ne; Typ dveřní zarážky: Bez; Typ samozavírače: Hřebenový s kluznou lištou + požární konzole; Vzduchová neprůzvučnost: 0; Dveře_Světlá-šířka: 0.9 m; Dveře_Světlá-výška: 0 m; Zárubeň/Rám_Typ: dvoudílná; Zárubeň/Rám_Materiál: Ocelová; Zárubeň/Rám_Povrch: komaxit; Křídlo_Materiál: Dřevěné; Křídlo_Povrch_Int.: HPL laminát; Křídlo_Povrch_Ext.: HPL laminát; Kování_Klika_Int.: klika; Kování_Klika_Ext.: paniková klika; Kování_Zámek: mechanický vložkový; Specifikace: Interiérové dveře dvoukřídlé prosklené; Allright_Stavebni_dil_ID: 1364Obj0798609541; Jednotka: Kus; Název_objektu: Dveře - objekt+SmartPart; GlassSurface: 1.69598; HeightWindowSillOutside: 0; HeightWindowSillInside: 0; OffsetOpeningBottom: 0; OffsetOpeningTop: 0; OffsetOpeningLeft: 0; OffsetOpeningRight: 0; DeductionOpeningBottom: 100; DeductionOpeningLeft: 50; DeductionOpeningRight: 50; DeductionOpeningTop: 50
Pset_DoorCommon - Status: NEW; IsExternal: no; FireRating: EI 30DP3-Sm-C; ThermalTransmittance: 0 W/K/m2; HandicapAccessible: no; SmokeStop: no; SelfClosing: no; FireExit: no; SecurityRating: bez
Qto_DoorBaseQuantities - Height: 2.12 m; Width: 1.55 m; Area: 3.286 m2; Perimeter: 0 m

# IfcDoor: I.D002
In: Půdorys 1.PP
Type - PredefinedType: DOOR; ParameterTakesPrecedence: no
OverallHeight: 2.12 m; OverallWidth: 1.2 m
NEMSOK - Kód prvku: DD01.02.0002; Jednotková_cena: 0; V6: 0 m; V7: 0 m; V8: 0 m; V9: 0; Verze programu: 2.2; Označení: I.D002; Plugin_Bezeichnung: MainObject; Plugin_Objektname: SmartPartCompressed; Uvažované procento prosklení: 0; Verze: 4.0; Podlaží: 1.PP; šířka: 1100; výška: 1970; Funkce (venkovní): Ne; Připojení EZS: Ne; Připojení NN: Ne; Připojení EPS: Ne; Připojení MaR: Ne; Připojení ACS: Ne; Typ dveřní zarážky: Bez; Typ samozavírače: Bez; Vzduchová neprůzvučnost: 32; Dveře_Světlá-šířka: 0 m; Dveře_Světlá-výška: 0 m; Zárubeň/Rám_Typ: dvoudílná; Zárubeň/Rám_Materiál: Ocelová; Zárubeň/Rám_Povrch: komaxit; Křídlo_Materiál: Dřevěné; Křídlo_Povrch_Int.: HPL laminát; Křídlo_Povrch_Ext.: HPL laminát; Kování_Klika_Int.: klika; Kování_Klika_Ext.: koule; Kování_Zámek: mechanický vložkový; Specifikace: Interiérové dveře jednokřídlé plné; Allright_Stavebni_dil_ID: 1364Obj0000007829; Jednotka: Kus; Název_objektu: Dveře - objekt+SmartPart; GlassSurface: 0.12; HeightWindowSillOutside: 0; HeightWindowSillInside: 0; OffsetOpeningBottom: 0; OffsetOpeningTop: 0; OffsetOpeningLeft: 0; OffsetOpeningRight: 0; DeductionOpeningBottom: 100; DeductionOpeningLeft: 50; DeductionOpeningRight: 50; DeductionOpeningTop: 50
Pset_DoorCommon - Status: NEW; IsExternal: no; ThermalTransmittance: 0 W/K/m2; AcousticRating: 32 dB; HandicapAccessible: no; SmokeStop: no; SelfClosing: no; FireExit: no; SecurityRating: bez
Qto_DoorBaseQuantities - Height: 2.12 m; Width: 1.2 m; Area: 2.544 m2; Perimeter: 0 m

# IfcDoor: I.D003
In: Půdorys 1.PP
Type - PredefinedType: DOOR; ParameterTakesPrecedence: no
OverallHeight: 2.05 m; OverallWidth: 1 m
NEMSOK - Kód prvku: DD01.02.0003; Jednotková_cena: 0; V6: 0 m; V7: 0 m; V8: 0 m; V9: 0; Verze programu: 2.2; Označení: I.D003; Plugin_Bezeichnung: MainObject; Plugin_Objektname: SmartPartCompressed; Uvažované procento prosklení: 0; Verze: 4.0; Podlaží: 1.PP; šířka: 900; výška: 2000; Funkce (venkovní): Ne; Připojení EZS: Ne; Připojení NN: Ne; Připojení EPS: Ne; Připojení MaR: Ne; Připojení ACS: Ne; Typ dveřní zarážky: Bez; Typ samozavírače: Bez; Vzduchová neprůzvučnost: 32; Dveře_Světlá-šířka: 0 m; Dveře_Světlá-výška: 0 m; Zárubeň/Rám_Typ: dvoudílná; Zárubeň/Rám_Materiál: Ocelová; Zárubeň/Rám_Povrch: komaxit; Křídlo_Materiál: Dřevěné; Křídlo_Povrch_Int.: HPL laminát; Křídlo_Povrch_Ext.: HPL laminát; Kování_Klika_Int.: klika; Kování_Klika_Ext.: klika; Kování_Zámek: mechanický vložkový; Specifikace: Interiérové dveře jednokřídlé plné; Allright_Stavebni_dil_ID: 1364Obj0000006691; Jednotka: Kus; Název_objektu: Dveře - objekt+SmartPart; GlassSurface: 0; HeightWindowSillOutside: 0; HeightWindowSillInside: 0; OffsetOpeningBottom: 0; OffsetOpeningTop: 0; OffsetOpeningLeft: 0; OffsetOpeningRight: 0; DeductionOpeningBottom: 0; DeductionOpeningLeft: 50; DeductionOpeningRight: 50; DeductionOpeningTop: 50
Pset_DoorCommon - Status: NEW; IsExternal: no; ThermalTransmittance: 0 W/K/m2; AcousticRating: 32 dB; HandicapAccessible: no; SmokeStop: no; SelfClosing: no; FireExit: no; SecurityRating: bez
Qto_DoorBaseQuantities - Height: 2.05 m; Width: 1 m; Area: 2.05 m2; Perimeter: 0 m

# IfcDoor: I.D004
In: Půdorys 1.PP
Type - PredefinedType: DOOR; ParameterTakesPrecedence: no
OverallHeight: 2.12 m; OverallWidth: 1.2 m
NEMSOK - Kód prvku: DD01.02.0004; Jednotková_cena: 0; V6: 0 m; V7: 0 m; V8: 0 m; V9: 0; Verze programu: 2.2; Označení: I.D004; Plugin_Bezeichnung: MainObject; Plugin_Objektname: SmartPartCompressed; Uvažované procento prosklení: 0; Verze: 4.0; Podlaží: 1.PP; šířka: 1100; výška: 1970; Funkce (venkovní): Ne; Připojení EZS: Ne; Připojení NN: Ne; Připojení EPS: Ne; Připojení MaR: Ne; Připojení ACS: Ne; Typ dveřní zarážky: Bez; Typ samozavírače: Bez; Vzduchová neprůzvučnost: 32; Dveře_Světlá-šířka: 0 m; Dveře_Světlá-výška: 0 m; Zárubeň/Rám_Typ: dvoudílná; Zárubeň/Rám_Materiál: Ocelová; Zárubeň/Rám_Povrch: komaxit; Křídlo_Materiál: Dřevěné; Křídlo_Povrch_Int.: HPL laminát; Křídlo_Povrch_Ext.: HPL laminát; Kování_Klika_Int.: klika; Kování_Klika_Ext.: koule; Kování_Zámek: mechanický vložkový; Specifikace: Interiérové dveře jednokřídlé plné; Allright_Stavebni_dil_ID: 1364Obj0000007779; Jednotka: Kus; Název_objektu: Dveře - objekt+SmartPart; GlassSurface: 0.12; HeightWindowSillOutside: 0; HeightWindowSillInside: 0; OffsetOpeningBottom: 0; OffsetOpeningTop: 0; OffsetOpeningLeft: 0; OffsetOpeningRight: 0; DeductionOpeningBottom: 100; DeductionOpeningLeft: 50; DeductionOpeningRight: 50; DeductionOpeningTop: 50
Pset_DoorCommon - Status: NEW; IsExternal: no; ThermalTransmittance: 0 W/K/m2; AcousticRating: 32 dB; HandicapAccessible: no; SmokeStop: no; SelfClosing: no; FireExit: no; SecurityRating: bez
Qto_DoorBaseQuantities - Height: 2.12 m; Width: 1.2 m; Area: 2.544 m2; Perimeter: 0 m

# IfcDoor: I.D005
In: Půdorys 1.PP
Type - PredefinedType: DOOR; ParameterTakesPrecedence: no
OverallHeight: 2.12 m; OverallWidth: 1 m
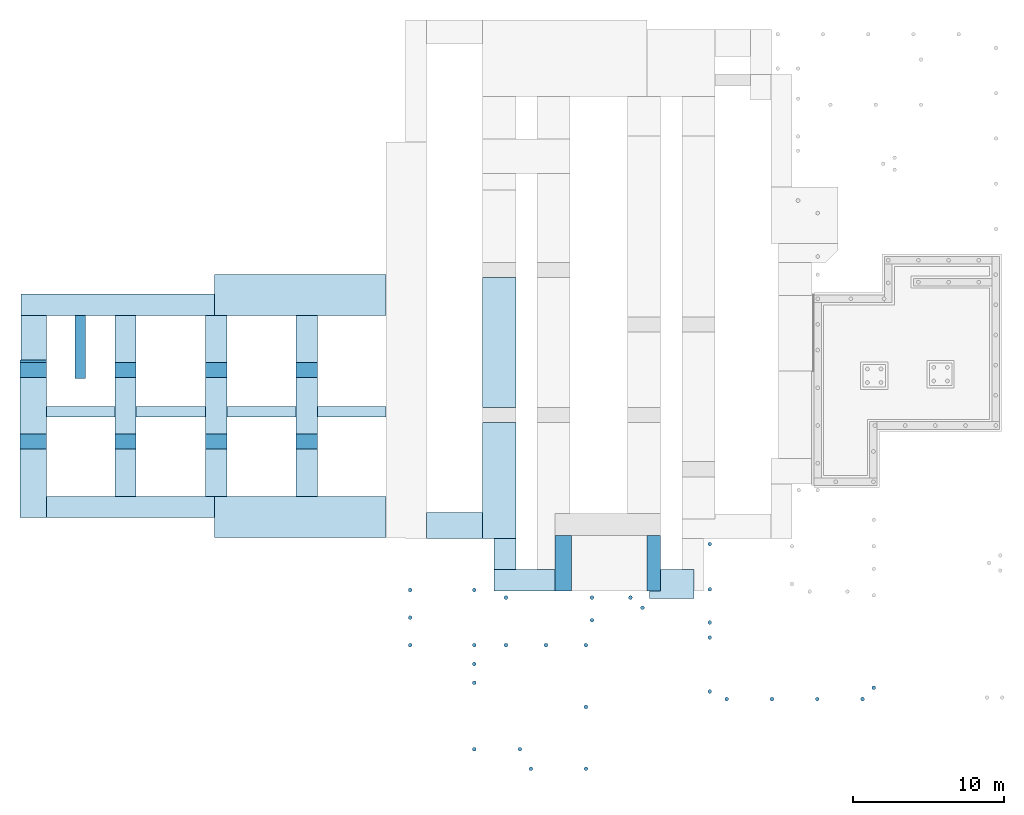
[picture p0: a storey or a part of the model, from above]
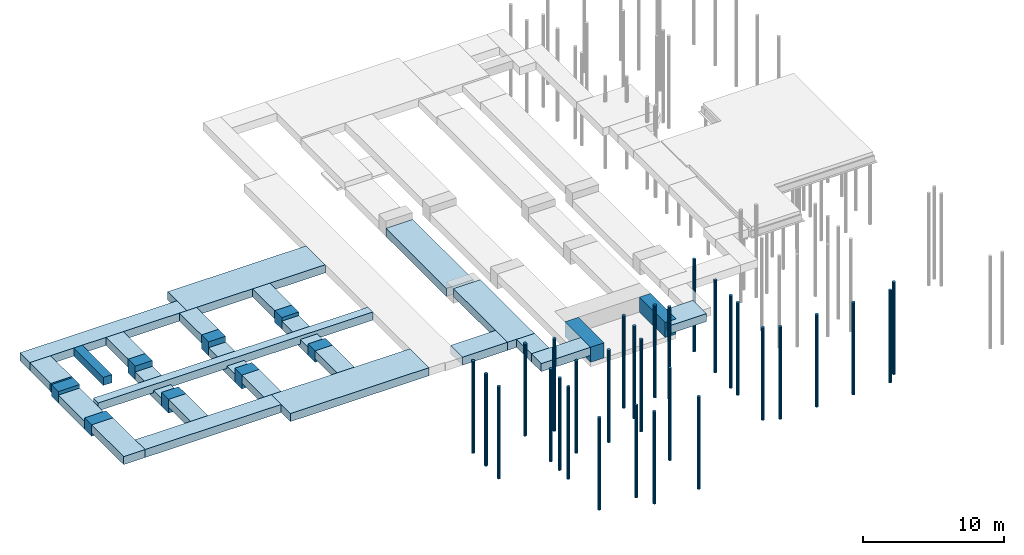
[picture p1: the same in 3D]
Properties of the parts of a building model (IFC4), part 9 of 45

# IfcDoor: I.D005
NEMSOK - Kód prvku: DD01.02.0005; Jednotková_cena: 0; V6: 0 m; V7: 0 m; V8: 0 m; V9: 0; Verze programu: 2.2; Označení: I.D005; Plugin_Bezeichnung: MainObject; Plugin_Objektname: SmartPartCompressed; Uvažované procento prosklení: 0; Verze: 4.0; Podlaží: 1.PP; šířka: 900; výška: 1970; Funkce (venkovní): Ne; Připojení EZS: Ne; Připojení NN: Ne; Připojení EPS: Ne; Připojení MaR: Ne; Připojení ACS: Ne; Typ dveřní zarážky: Bez; Typ samozavírače: Bez; Vzduchová neprůzvučnost: 32; Dveře_Světlá-šířka: 0 m; Dveře_Světlá-výška: 0 m; Zárubeň/Rám_Typ: dvoudílná; Zárubeň/Rám_Materiál: Ocelová; Zárubeň/Rám_Povrch: komaxit; Křídlo_Materiál: Dřevěné; Křídlo_Povrch_Int.: HPL laminát; Křídlo_Povrch_Ext.: HPL laminát; Kování_Klika_Int.: klika; Kování_Klika_Ext.: klika; Kování_Zámek: mechanický vložkový; Specifikace: Interiérové dveře jednokřídlé plné; Allright_Stavebni_dil_ID: 1364Obj0000004208; Jednotka: Kus; Název_objektu: Dveře - objekt+SmartPart; GlassSurface: 0.1; HeightWindowSillOutside: 0; HeightWindowSillInside: 0; OffsetOpeningBottom: 0; OffsetOpeningTop: 0; OffsetOpeningLeft: 0; OffsetOpeningRight: 0; DeductionOpeningBottom: 100; DeductionOpeningLeft: 50; DeductionOpeningRight: 50; DeductionOpeningTop: 50
Pset_DoorCommon - Status: NEW; IsExternal: no; ThermalTransmittance: 0 W/K/m2; AcousticRating: 32 dB; HandicapAccessible: no; SmokeStop: no; SelfClosing: no; FireExit: no; SecurityRating: bez
Qto_DoorBaseQuantities - Height: 2.12 m; Width: 1 m; Area: 2.12 m2; Perimeter: 0 m

# IfcDoor: I.D006
In: Půdorys 1.PP
Type - PredefinedType: DOOR; ParameterTakesPrecedence: no
OverallHeight: 2.12 m; OverallWidth: 1 m
NEMSOK - Kód prvku: DD01.02.0006; Jednotková_cena: 0; V6: 0 m; V7: 0 m; V8: 0 m; V9: 0; Verze programu: 2.2; Označení: I.D006; Plugin_Bezeichnung: MainObject; Plugin_Objektname: SmartPartCompressed; Uvažované procento prosklení: 0; Verze: 4.0; Podlaží: 1.PP; šířka: 900; výška: 1970; Funkce (venkovní): Ne; Připojení EZS: Ne; Připojení NN: Ne; Připojení EPS: Ne; Připojení MaR: Ne; Připojení ACS: Ne; Typ dveřní zarážky: Bez; Typ samozavírače: Bez; Vzduchová neprůzvučnost: 32; Dveře_Světlá-šířka: 0 m; Dveře_Světlá-výška: 0 m; Zárubeň/Rám_Typ: dvoudílná; Zárubeň/Rám_Materiál: Ocelová; Zárubeň/Rám_Povrch: komaxit; Křídlo_Materiál: Dřevěné; Křídlo_Povrch_Int.: HPL laminát; Křídlo_Povrch_Ext.: HPL laminát; Kování_Klika_Int.: klika; Kování_Klika_Ext.: koule; Kování_Zámek: mechanický vložkový; Specifikace: Interiérové dveře jednokřídlé plné; Allright_Stavebni_dil_ID: 1364Obj0000007931; Jednotka: Kus; Název_objektu: Dveře - objekt+SmartPart; GlassSurface: 0.1; HeightWindowSillOutside: 0; HeightWindowSillInside: 0; OffsetOpeningBottom: 0; OffsetOpeningTop: 0; OffsetOpeningLeft: 0; OffsetOpeningRight: 0; DeductionOpeningBottom: 100; DeductionOpeningLeft: 50; DeductionOpeningRight: 50; DeductionOpeningTop: 50
Pset_DoorCommon - Status: NEW; IsExternal: no; ThermalTransmittance: 0 W/K/m2; AcousticRating: 32 dB; HandicapAccessible: no; SmokeStop: no; SelfClosing: no; FireExit: no; SecurityRating: bez
Qto_DoorBaseQuantities - Height: 2.12 m; Width: 1 m; Area: 2.12 m2; Perimeter: 0 m

# IfcDoor: I.D007
In: Půdorys 1.PP
Type - PredefinedType: DOOR; ParameterTakesPrecedence: no
OverallHeight: 2.12 m; OverallWidth: 1.2 m
NEMSOK - Kód prvku: DD01.02.0007; Jednotková_cena: 0; V6: 0 m; V7: 0 m; V8: 0 m; V9: 0; Verze programu: 2.2; Označení: I.D007; Plugin_Bezeichnung: MainObject; Plugin_Objektname: SmartPartCompressed; Uvažované procento prosklení: 0; Verze: 4.0; Podlaží: 1.PP; šířka: 1100; výška: 1970; Funkce (venkovní): Ne; Připojení EZS: Ne; Připojení NN: Ne; Připojení EPS: Ne; Připojení MaR: Ne; Připojení ACS: Ne; Typ dveřní zarážky: Bez; Typ samozavírače: Bez; Vzduchová neprůzvučnost: 32; Dveře_Světlá-šířka: 0 m; Dveře_Světlá-výška: 0 m; Zárubeň/Rám_Typ: dvoudílná; Zárubeň/Rám_Materiál: Ocelová; Zárubeň/Rám_Povrch: komaxit; Křídlo_Materiál: Dřevěné; Křídlo_Povrch_Int.: HPL laminát; Křídlo_Povrch_Ext.: HPL laminát; Kování_Klika_Int.: klika; Kování_Klika_Ext.: koule; Kování_Zámek: mechanický vložkový; Specifikace: Interiérové dveře jednokřídlé plné; Allright_Stavebni_dil_ID: 1364Obj0000007881; Jednotka: Kus; Název_objektu: Dveře - objekt+SmartPart; GlassSurface: 0.12; HeightWindowSillOutside: 0; HeightWindowSillInside: 0; OffsetOpeningBottom: 0; OffsetOpeningTop: 0; OffsetOpeningLeft: 0; OffsetOpeningRight: 0; DeductionOpeningBottom: 100; DeductionOpeningLeft: 50; DeductionOpeningRight: 50; DeductionOpeningTop: 50
Pset_DoorCommon - Status: NEW; IsExternal: no; ThermalTransmittance: 0 W/K/m2; AcousticRating: 32 dB; HandicapAccessible: no; SmokeStop: no; SelfClosing: no; FireExit: no; SecurityRating: bez
Qto_DoorBaseQuantities - Height: 2.12 m; Width: 1.2 m; Area: 2.544 m2; Perimeter: 0 m

# IfcDoor: I.D008
In: Půdorys 1.PP
Type - PredefinedType: DOOR; ParameterTakesPrecedence: no
OverallHeight: 2.12 m; OverallWidth: 1.2 m
NEMSOK - Kód prvku: DD01.02.0008; Jednotková_cena: 0; V6: 0 m; V7: 0 m; V8: 0 m; V9: 0; Verze programu: 2.2; Označení: I.D008; Plugin_Bezeichnung: MainObject; Plugin_Objektname: SmartPartCompressed; Uvažované procento prosklení: 0; Verze: 4.0; Podlaží: 1.PP; šířka: 1100; výška: 1970; Funkce (venkovní): Ne; Připojení EZS: Ne; Připojení NN: Ne; Připojení EPS: Ne; Připojení MaR: Ne; Připojení ACS: Ne; Typ dveřní zarážky: Bez; Typ samozavírače: Bez; Vzduchová neprůzvučnost: 32; Dveře_Světlá-šířka: 0 m; Dveře_Světlá-výška: 0 m; Zárubeň/Rám_Typ: dvoudílná; Zárubeň/Rám_Materiál: Ocelová; Zárubeň/Rám_Povrch: komaxit; Křídlo_Materiál: Dřevěné; Křídlo_Povrch_Int.: HPL laminát; Křídlo_Povrch_Ext.: HPL laminát; Kování_Klika_Int.: klika; Kování_Klika_Ext.: koule; Kování_Zámek: mechanický vložkový; Specifikace: Interiérové dveře jednokřídlé plné; Allright_Stavebni_dil_ID: 1364Obj0000008297; Jednotka: Kus; Název_objektu: Dveře - objekt+SmartPart; GlassSurface: 0.12; HeightWindowSillOutside: 0; HeightWindowSillInside: 0; OffsetOpeningBottom: 0; OffsetOpeningTop: 0; OffsetOpeningLeft: 0; OffsetOpeningRight: 0; DeductionOpeningBottom: 100; DeductionOpeningLeft: 50; DeductionOpeningRight: 50; DeductionOpeningTop: 50
Pset_DoorCommon - Status: NEW; IsExternal: no; ThermalTransmittance: 0 W/K/m2; AcousticRating: 32 dB; HandicapAccessible: no; SmokeStop: no; SelfClosing: no; FireExit: no; SecurityRating: bez
Qto_DoorBaseQuantities - Height: 2.12 m; Width: 1.2 m; Area: 2.544 m2; Perimeter: 0 m

# IfcDoor: I.D009
In: Půdorys 1.PP
Type - PredefinedType: DOOR; ParameterTakesPrecedence: no
OverallHeight: 2.12 m; OverallWidth: 0.9 m
NEMSOK - Kód prvku: DD01.02.0009; Jednotková_cena: 0; V6: 0 m; V7: 0 m; V8: 0 m; V9: 0; Verze programu: 2.2; Označení: I.D009; Plugin_Bezeichnung: MainObject; Plugin_Objektname: SmartPartCompressed; Uvažované procento prosklení: 0; Verze: 4.0; Podlaží: 1.PP; šířka: 800; výška: 1970; Funkce (venkovní): Ne; Připojení EZS: Ne; Připojení NN: Ne; Připojení EPS: Ne; Připojení MaR: Ne; Připojení ACS: Ne; Typ dveřní zarážky: Bez; Typ samozavírače: Bez; Vzduchová neprůzvučnost: 32; Dveře_Světlá-šířka: 0 m; Dveře_Světlá-výška: 0 m; Zárubeň/Rám_Typ: dvoudílná; Zárubeň/Rám_Materiál: Ocelová; Zárubeň/Rám_Povrch: komaxit; Křídlo_Materiál: Dřevěné; Křídlo_Povrch_Int.: HPL laminát; Křídlo_Povrch_Ext.: HPL laminát; Kování_Klika_Int.: klika; Kování_Klika_Ext.: koule; Kování_Zámek: mechanický vložkový; Specifikace: Interiérové dveře jednokřídlé plné; Allright_Stavebni_dil_ID: 1364Obj0000010686; Jednotka: Kus; Název_objektu: Dveře - objekt+SmartPart; GlassSurface: 0.09; HeightWindowSillOutside: 0; HeightWindowSillInside: 0; OffsetOpeningBottom: 0; OffsetOpeningTop: 0; OffsetOpeningLeft: 0; OffsetOpeningRight: 0; DeductionOpeningBottom: 100; DeductionOpeningLeft: 50; DeductionOpeningRight: 50; DeductionOpeningTop: 50
Pset_DoorCommon - Status: NEW; IsExternal: no; ThermalTransmittance: 0 W/K/m2; AcousticRating: 32 dB; HandicapAccessible: no; SmokeStop: no; SelfClosing: no; FireExit: no; SecurityRating: bez
Qto_DoorBaseQuantities - Height: 2.12 m; Width: 0.9 m; Area: 1.908 m2; Perimeter: 0 m

# IfcDoor: I.D010
In: Půdorys 1.PP
Type - PredefinedType: DOOR; ParameterTakesPrecedence: no
OverallHeight: 2.12 m; OverallWidth: 0.9 m
NEMSOK - Kód prvku: DD01.02.0010; Jednotková_cena: 0; V6: 0 m; V7: 0 m; V8: 0 m; V9: 0; Verze programu: 2.2; Označení: I.D010; Plugin_Bezeichnung: MainObject; Plugin_Objektname: SmartPartCompressed; Uvažované procento prosklení: 0; Verze: 4.0; Podlaží: 1.PP; šířka: 800; výška: 1970; Funkce (venkovní): Ne; Připojení EZS: Ne; Připojení NN: Ne; Připojení EPS: Ne; Připojení MaR: Ne; Připojení ACS: Ne; Typ dveřní zarážky: Bez; Typ samozavírače: Hřebenový s kluznou lištou; Vzduchová neprůzvučnost: 0; Dveře_Světlá-šířka: 0 m; Dveře_Světlá-výška: 0 m; Zárubeň/Rám_Typ: dvoudílná; Zárubeň/Rám_Materiál: Ocelová; Zárubeň/Rám_Povrch: komaxit; Křídlo_Materiál: Dřevěné; Křídlo_Povrch_Int.: HPL laminát; Křídlo_Povrch_Ext.: HPL laminát; Kování_Klika_Int.: klika; Kování_Klika_Ext.: klika; Kování_Zámek: mechanický vložkový; Specifikace: Interiérové dveře jednokřídlé plné; Allright_Stavebni_dil_ID: 1364Obj0000011121; Jednotka: Kus; Název_objektu: Dveře - objekt+SmartPart; GlassSurface: 0.09; HeightWindowSillOutside: 0; HeightWindowSillInside: 0; OffsetOpeningBottom: 0; OffsetOpeningTop: 0; OffsetOpeningLeft: 0; OffsetOpeningRight: 0; DeductionOpeningBottom: 100; DeductionOpeningLeft: 50; DeductionOpeningRight: 50; DeductionOpeningTop: 50
Pset_DoorCommon - Status: NEW; IsExternal: no; ThermalTransmittance: 0 W/K/m2; HandicapAccessible: no; SmokeStop: no; SelfClosing: no; FireExit: no; SecurityRating: bez
Qto_DoorBaseQuantities - Height: 2.12 m; Width: 0.9 m; Area: 1.908 m2; Perimeter: 0 m

# IfcDoor: I.D011
In: Půdorys 1.PP
Type - PredefinedType: DOOR; ParameterTakesPrecedence: no
OverallHeight: 2.12 m; OverallWidth: 0.8 m
NEMSOK - Kód prvku: DD01.02.0011; Jednotková_cena: 0; V6: 0 m; V7: 0 m; V8: 0 m; V9: 0; Verze programu: 2.2; Označení: I.D011; Plugin_Bezeichnung: MainObject; Plugin_Objektname: SmartPartCompressed; Uvažované procento prosklení: 0; Verze: 4.0; Podlaží: 1.PP; šířka: 700; výška: 1970; Funkce (venkovní): Ne; Připojení EZS: Ne; Připojení NN: Ne; Připojení EPS: Ne; Připojení MaR: Ne; Připojení ACS: Ne; Typ dveřní zarážky: Plastová nástěnná; Typ samozavírače: Bez; Vzduchová neprůzvučnost: 0; Dveře_Světlá-šířka: 0 m; Dveře_Světlá-výška: 0 m; Zárubeň/Rám_Typ: dvoudílná; Zárubeň/Rám_Materiál: Ocelová; Zárubeň/Rám_Povrch: komaxit; Křídlo_Materiál: Dřevěné; Křídlo_Povrch_Int.: HPL laminát; Křídlo_Povrch_Ext.: HPL laminát; Kování_Klika_Int.: klika; Kování_Klika_Ext.: klika; Kování_Zámek: mechanický vložkový; Specifikace: Interiérové dveře jednokřídlé plné; Allright_Stavebni_dil_ID: 1364Obj0000010616; Jednotka: Kus; Název_objektu: Dveře - objekt+SmartPart; GlassSurface: 0.08; HeightWindowSillOutside: 0; HeightWindowSillInside: 0; OffsetOpeningBottom: 0; OffsetOpeningTop: 0; OffsetOpeningLeft: 0; OffsetOpeningRight: 0; DeductionOpeningBottom: 100; DeductionOpeningLeft: 50; DeductionOpeningRight: 50; DeductionOpeningTop: 50
Pset_DoorCommon - Status: NEW; IsExternal: no; ThermalTransmittance: 0 W/K/m2; HandicapAccessible: no; SmokeStop: no; SelfClosing: no; FireExit: no; SecurityRating: bez
Qto_DoorBaseQuantities - Height: 2.12 m; Width: 0.8 m; Area: 1.696 m2; Perimeter: 0 m

# IfcDoor: I.D012
In: Půdorys 1.PP
Type - PredefinedType: DOOR; ParameterTakesPrecedence: no
OverallHeight: 2.12 m; OverallWidth: 0.9 m
NEMSOK - Kód prvku: DD01.02.0012; Jednotková_cena: 0; V6: 0 m; V7: 0 m; V8: 0 m; V9: 0; Verze programu: 2.2; Označení: I.D012; Plugin_Bezeichnung: MainObject; Plugin_Objektname: SmartPartCompressed; Uvažované procento prosklení: 0; Verze: 4.0; Podlaží: 1.PP; šířka: 800; výška: 1970; Funkce (venkovní): Ne; Připojení EZS: Ne; Připojení NN: Ne; Připojení EPS: Ne; Připojení MaR: Ne; Připojení ACS: Ne; Typ dveřní zarážky: Bez; Typ samozavírače: Hřebenový s kluznou lištou; Vzduchová neprůzvučnost: 0; Dveře_Světlá-šířka: 0 m; Dveře_Světlá-výška: 0 m; Zárubeň/Rám_Typ: dvoudílná; Zárubeň/Rám_Materiál: Ocelová; Zárubeň/Rám_Povrch: komaxit; Křídlo_Materiál: Dřevěné; Křídlo_Povrch_Int.: HPL laminát; Křídlo_Povrch_Ext.: HPL laminát; Kování_Klika_Int.: klika; Kování_Klika_Ext.: klika; Kování_Zámek: WC zámek; Specifikace: Interiérové dveře jednokřídlé plné; Allright_Stavebni_dil_ID: 1364Obj0000011124; Jednotka: Kus; Název_objektu: Dveře - objekt+SmartPart; GlassSurface: 0.09; HeightWindowSillOutside: 0; HeightWindowSillInside: 0; OffsetOpeningBottom: 0; OffsetOpeningTop: 0; OffsetOpeningLeft: 0; OffsetOpeningRight: 0; DeductionOpeningBottom: 100; DeductionOpeningLeft: 50; DeductionOpeningRight: 50; DeductionOpeningTop: 50
Pset_DoorCommon - Status: NEW; IsExternal: no; ThermalTransmittance: 0 W/K/m2; HandicapAccessible: no; SmokeStop: no; SelfClosing: no; FireExit: no; SecurityRating: bez
Qto_DoorBaseQuantities - Height: 2.12 m; Width: 0.9 m; Area: 1.908 m2; Perimeter: 0 m

# IfcDoor: I.D013
In: Půdorys 1.PP
Type - PredefinedType: DOOR; ParameterTakesPrecedence: no
OverallHeight: 2.12 m; OverallWidth: 0.9 m
NEMSOK - Kód prvku: DD01.02.0013; Jednotková_cena: 0; V6: 0 m; V7: 0 m; V8: 0 m; V9: 0; Verze programu: 2.2; Označení: I.D013; Plugin_Bezeichnung: MainObject; Plugin_Objektname: SmartPartCompressed; Uvažované procento prosklení: 0; Verze: 4.0; Podlaží: 1.PP; šířka: 800; výška: 1970; Funkce (venkovní): Ne; Připojení EZS: Ne; Připojení NN: Ne; Připojení EPS: Ne; Připojení MaR: Ne; Připojení ACS: Ne; Typ dveřní zarážky: Bez; Typ samozavírače: Hřebenový s kluznou lištou; Vzduchová neprůzvučnost: 0; Dveře_Světlá-šířka: 0 m; Dveře_Světlá-výška: 0 m; Zárubeň/Rám_Typ: dvoudílná; Zárubeň/Rám_Materiál: Ocelová; Zárubeň/Rám_Povrch: komaxit; Křídlo_Materiál: Dřevěné; Křídlo_Povrch_Int.: HPL laminát; Křídlo_Povrch_Ext.: HPL laminát; Kování_Klika_Int.: klika; Kování_Klika_Ext.: klika; Kování_Zámek: mechanický vložkový; Specifikace: Interiérové dveře jednokřídlé plné; Allright_Stavebni_dil_ID: 1364Obj0000010738; Jednotka: Kus; Název_objektu: Dveře - objekt+SmartPart; GlassSurface: 0.09; HeightWindowSillOutside: 0; HeightWindowSillInside: 0; OffsetOpeningBottom: 0; OffsetOpeningTop: 0; OffsetOpeningLeft: 0; OffsetOpeningRight: 0; DeductionOpeningBottom: 100; DeductionOpeningLeft: 50; DeductionOpeningRight: 50; DeductionOpeningTop: 50
Pset_DoorCommon - Status: NEW; IsExternal: no; ThermalTransmittance: 0 W/K/m2; HandicapAccessible: no; SmokeStop: no; SelfClosing: no; FireExit: no; SecurityRating: bez
Qto_DoorBaseQuantities - Height: 2.12 m; Width: 0.9 m; Area: 1.908 m2; Perimeter: 0 m

# IfcDoor: I.D014
In: Půdorys 1.PP
Type - PredefinedType: DOOR; ParameterTakesPrecedence: no
OverallHeight: 2.12 m; OverallWidth: 0.8 m
NEMSOK - Kód prvku: DD01.02.0014; Jednotková_cena: 0; V6: 0 m; V7: 0 m; V8: 0 m; V9: 0; Verze programu: 2.2; Označení: I.D014; Plugin_Bezeichnung: MainObject; Plugin_Objektname: SmartPartCompressed; Uvažované procento prosklení: 0; Verze: 4.0; Podlaží: 1.PP; šířka: 700; výška: 1970; Funkce (venkovní): Ne; Připojení EZS: Ne; Připojení NN: Ne; Připojení EPS: Ne; Připojení MaR: Ne; Připojení ACS: Ne; Typ dveřní zarážky: Bez; Typ samozavírače: Bez; Vzduchová neprůzvučnost: 0; Dveře_Světlá-šířka: 0 m; Dveře_Světlá-výška: 0 m; Zárubeň/Rám_Typ: dvoudílná; Zárubeň/Rám_Materiál: Ocelová; Zárubeň/Rám_Povrch: komaxit; Křídlo_Materiál: Dřevěné; Křídlo_Povrch_Int.: HPL laminát; Křídlo_Povrch_Ext.: HPL laminát; Kování_Klika_Int.: klika; Kování_Klika_Ext.: klika; Kování_Zámek: WC zámek; Specifikace: Interiérové dveře jednokřídlé plné; Allright_Stavebni_dil_ID: 1364Obj0000010764; Jednotka: Kus; Název_objektu: Dveře - objekt+SmartPart; GlassSurface: 0.08; HeightWindowSillOutside: 0; HeightWindowSillInside: 0; OffsetOpeningBottom: 0; OffsetOpeningTop: 0; OffsetOpeningLeft: 0; OffsetOpeningRight: 0; DeductionOpeningBottom: 100; DeductionOpeningLeft: 50; DeductionOpeningRight: 50; DeductionOpeningTop: 50
Pset_DoorCommon - Status: NEW; IsExternal: no; ThermalTransmittance: 0 W/K/m2; HandicapAccessible: no; SmokeStop: no; SelfClosing: no; FireExit: no; SecurityRating: bez
Qto_DoorBaseQuantities - Height: 2.12 m; Width: 0.8 m; Area: 1.696 m2; Perimeter: 0 m

# IfcDoor: I.D015
In: Půdorys 1.PP
Type - PredefinedType: DOOR; ParameterTakesPrecedence: no
OverallHeight: 2.12 m; OverallWidth: 0.8 m
NEMSOK - Kód prvku: DD01.02.0015; Jednotková_cena: 0; V6: 0 m; V7: 0 m; V8: 0 m; V9: 0; Verze programu: 2.2; Označení: I.D015; Plugin_Bezeichnung: MainObject; Plugin_Objektname: SmartPartCompressed; Uvažované procento prosklení: 0; Verze: 4.0; Podlaží: 1.PP; šířka: 700; výška: 1970; Funkce (venkovní): Ne; Připojení EZS: Ne; Připojení NN: Ne; Připojení EPS: Ne; Připojení MaR: Ne; Připojení ACS: Ne; Typ dveřní zarážky: Plastová nástěnná; Typ samozavírače: Bez; Vzduchová neprůzvučnost: 0; Dveře_Světlá-šířka: 0 m; Dveře_Světlá-výška: 0 m; Zárubeň/Rám_Typ: dvoudílná; Zárubeň/Rám_Materiál: Ocelová; Zárubeň/Rám_Povrch: komaxit; Křídlo_Materiál: Dřevěné; Křídlo_Povrch_Int.: HPL laminát; Křídlo_Povrch_Ext.: HPL laminát; Kování_Klika_Int.: klika; Kování_Klika_Ext.: klika; Kování_Zámek: WC zámek; Specifikace: Interiérové dveře jednokřídlé plné; Allright_Stavebni_dil_ID: 1364Obj0000010757; Jednotka: Kus; Název_objektu: Dveře - objekt+SmartPart; GlassSurface: 0.08; HeightWindowSillOutside: 0; HeightWindowSillInside: 0; OffsetOpeningBottom: 0; OffsetOpeningTop: 0; OffsetOpeningLeft: 0; OffsetOpeningRight: 0; DeductionOpeningBottom: 100; DeductionOpeningLeft: 50; DeductionOpeningRight: 50; DeductionOpeningTop: 50
Pset_DoorCommon - Status: NEW; IsExternal: no; ThermalTransmittance: 0 W/K/m2; HandicapAccessible: no; SmokeStop: no; SelfClosing: no; FireExit: no; SecurityRating: bez
Qto_DoorBaseQuantities - Height: 2.12 m; Width: 0.8 m; Area: 1.696 m2; Perimeter: 0 m

# IfcDoor: I.D017
In: Půdorys 1.PP
Type - PredefinedType: DOOR; ParameterTakesPrecedence: no
OverallHeight: 2.12 m; OverallWidth: 1 m
NEMSOK - Kód prvku: DD01.02.0017; Jednotková_cena: 0; V6: 0 m; V7: 0 m; V8: 0 m; V9: 0; Verze programu: 2.2; Označení: I.D017; Plugin_Bezeichnung: MainObject; Plugin_Objektname: SmartPartCompressed; Uvažované procento prosklení: 0; Verze: 4.0; Podlaží: 1.PP; šířka: 900; výška: 1970; Funkce (venkovní): Ne; Připojení EZS: Ne; Připojení NN: Ne; Připojení EPS: Ne; Připojení MaR: Ne; Připojení ACS: Ne; Typ dveřní zarážky: Plastová nástěnná; Typ samozavírače: Bez; Vzduchová neprůzvučnost: 32; Dveře_Světlá-šířka: 0 m; Dveře_Světlá-výška: 0 m; Zárubeň/Rám_Typ: pro zazdění; Zárubeň/Rám_Materiál: Ocelová; Zárubeň/Rám_Povrch: komaxit; Křídlo_Materiál: Dřevěné; Křídlo_Povrch_Int.: HPL laminát; Křídlo_Povrch_Ext.: HPL laminát; Kování_Klika_Int.: klika; Kování_Klika_Ext.: koule; Kování_Zámek: mechanický vložkový; Specifikace: Interiérové dveře jednokřídlé plné; Allright_Stavebni_dil_ID: 1364Obj0798521616; Jednotka: Kus; Název_objektu: Dveře - objekt+SmartPart; GlassSurface: 0.1; HeightWindowSillOutside: 0; HeightWindowSillInside: 0; OffsetOpeningBottom: 0; OffsetOpeningTop: 0; OffsetOpeningLeft: 0; OffsetOpeningRight: 0; DeductionOpeningBottom: 100; DeductionOpeningLeft: 50; DeductionOpeningRight: 50; DeductionOpeningTop: 50
Pset_DoorCommon - Status: NEW; IsExternal: no; ThermalTransmittance: 0 W/K/m2; AcousticRating: 32 dB; HandicapAccessible: no; SmokeStop: no; SelfClosing: no; FireExit: no; SecurityRating: bez
Qto_DoorBaseQuantities - Height: 2.12 m; Width: 1 m; Area: 2.12 m2; Perimeter: 0 m

# IfcDoor: I.D018
In: Půdorys 1.PP
Type - PredefinedType: DOOR; ParameterTakesPrecedence: no
OverallHeight: 2.12 m; OverallWidth: 0.8 m
NEMSOK - Kód prvku: DD01.02.0018; Jednotková_cena: 0; V6: 0 m; V7: 0 m; V8: 0 m; V9: 0; Verze programu: 2.2; Označení: I.D018; Plugin_Bezeichnung: MainObject; Plugin_Objektname: SmartPartCompressed; Uvažované procento prosklení: 0; Verze: 4.0; Podlaží: 1.PP; šířka: 700; výška: 1970; Funkce (venkovní): Ne; Připojení EZS: Ne; Připojení NN: Ne; Připojení EPS: Ne; Připojení MaR: Ne; Připojení ACS: Ne; Typ dveřní zarážky: Plastová nástěnná; Typ samozavírače: Hřebenový s kluznou lištou; Vzduchová neprůzvučnost: 0; Dveře_Světlá-šířka: 0 m; Dveře_Světlá-výška: 0 m; Zárubeň/Rám_Typ: pro zazdění; Zárubeň/Rám_Materiál: Ocelová; Zárubeň/Rám_Povrch: komaxit; Křídlo_Materiál: Dřevěné; Křídlo_Povrch_Int.: HPL laminát; Křídlo_Povrch_Ext.: HPL laminát; Kování_Klika_Int.: klika; Kování_Klika_Ext.: koule; Kování_Zámek: mechanický vložkový; Specifikace: Interiérové dveře jednokřídlé plné; Allright_Stavebni_dil_ID: 1364Obj0798521679; Jednotka: Kus; Název_objektu: Dveře - objekt+SmartPart; GlassSurface: 0.08; HeightWindowSillOutside: 0; HeightWindowSillInside: 0; OffsetOpeningBottom: 0; OffsetOpeningTop: 0; OffsetOpeningLeft: 0; OffsetOpeningRight: 0; DeductionOpeningBottom: 100; DeductionOpeningLeft: 50; DeductionOpeningRight: 50; DeductionOpeningTop: 50
Pset_DoorCommon - Status: NEW; IsExternal: no; ThermalTransmittance: 0 W/K/m2; HandicapAccessible: no; SmokeStop: no; SelfClosing: no; FireExit: no; SecurityRating: bez
Qto_DoorBaseQuantities - Height: 2.12 m; Width: 0.8 m; Area: 1.696 m2; Perimeter: 0 m

# IfcDoor: I.D019
In: Půdorys 1.PP
Type - PredefinedType: DOOR; ParameterTakesPrecedence: no
OverallHeight: 2.12 m; OverallWidth: 0.8 m
NEMSOK - Kód prvku: DD01.02.0019; Jednotková_cena: 0; V6: 0 m; V7: 0 m; V8: 0 m; V9: 0; Verze programu: 2.2; Označení: I.D019; Plugin_Bezeichnung: MainObject; Plugin_Objektname: SmartPartCompressed; Uvažované procento prosklení: 0; Verze: 4.0; Podlaží: 1.PP; šířka: 700; výška: 1970; Funkce (venkovní): Ne; Připojení EZS: Ne; Připojení NN: Ne; Připojení EPS: Ne; Připojení MaR: Ne; Připojení ACS: Ne; Typ dveřní zarážky: Plastová nástěnná; Typ samozavírače: Bez; Vzduchová neprůzvučnost: 0; Dveře_Světlá-šířka: 0 m; Dveře_Světlá-výška: 0 m; Zárubeň/Rám_Typ: dvoudílná; Zárubeň/Rám_Materiál: Ocelová; Zárubeň/Rám_Povrch: komaxit; Křídlo_Materiál: Dřevěné; Křídlo_Povrch_Int.: HPL laminát; Křídlo_Povrch_Ext.: HPL laminát; Kování_Klika_Int.: klika; Kování_Klika_Ext.: klika; Kování_Zámek: WC zámek; Specifikace: Interiérové dveře jednokřídlé plné; Allright_Stavebni_dil_ID: 1364Obj0000010034; Jednotka: Kus; Název_objektu: Dveře - objekt+SmartPart; GlassSurface: 0.08; HeightWindowSillOutside: 0; HeightWindowSillInside: 0; OffsetOpeningBottom: 0; OffsetOpeningTop: 0; OffsetOpeningLeft: 0; OffsetOpeningRight: 0; DeductionOpeningBottom: 100; DeductionOpeningLeft: 50; DeductionOpeningRight: 50; DeductionOpeningTop: 50
Pset_DoorCommon - Status: NEW; IsExternal: no; ThermalTransmittance: 0 W/K/m2; HandicapAccessible: no; SmokeStop: no; SelfClosing: no; FireExit: no; SecurityRating: bez
Qto_DoorBaseQuantities - Height: 2.12 m; Width: 0.8 m; Area: 1.696 m2; Perimeter: 0 m

# IfcDoor: I.D020
In: Půdorys 1.PP
Type - PredefinedType: DOOR; ParameterTakesPrecedence: no
OverallHeight: 2.12 m; OverallWidth: 1 m
NEMSOK - Kód prvku: DD01.02.0020; Jednotková_cena: 0; V6: 0 m; V7: 0 m; V8: 0 m; V9: 0; Verze programu: 2.2; Označení: I.D020; Plugin_Bezeichnung: MainObject; Plugin_Objektname: SmartPartCompressed; Uvažované procento prosklení: 0; Verze: 4.0; Podlaží: 1.PP; šířka: 900; výška: 1970; Funkce (venkovní): Ne; Připojení EZS: Ne; Připojení NN: Ne; Připojení EPS: Ne; Připojení MaR: Ne; Připojení ACS: Ne; Typ dveřní zarážky: Bez; Typ samozavírače: Bez; Vzduchová neprůzvučnost: 32; Dveře_Světlá-šířka: 0 m; Dveře_Světlá-výška: 0 m; Zárubeň/Rám_Typ: dvoudílná; Zárubeň/Rám_Materiál: Ocelová; Zárubeň/Rám_Povrch: komaxit; Křídlo_Materiál: Dřevěné; Křídlo_Povrch_Int.: HPL laminát; Křídlo_Povrch_Ext.: HPL laminát; Kování_Klika_Int.: klika; Kování_Klika_Ext.: klika; Kování_Zámek: mechanický vložkový; Specifikace: Interiérové dveře jednokřídlé plné; Allright_Stavebni_dil_ID: 1364Obj0000009927; Jednotka: Kus; Název_objektu: Dveře - objekt+SmartPart; GlassSurface: 0.1; HeightWindowSillOutside: 0; HeightWindowSillInside: 0; OffsetOpeningBottom: 0; OffsetOpeningTop: 0; OffsetOpeningLeft: 0; OffsetOpeningRight: 0; DeductionOpeningBottom: 100; DeductionOpeningLeft: 50; DeductionOpeningRight: 50; DeductionOpeningTop: 50
Pset_DoorCommon - Status: NEW; IsExternal: no; ThermalTransmittance: 0 W/K/m2; AcousticRating: 32 dB; HandicapAccessible: no; SmokeStop: no; SelfClosing: no; FireExit: no; SecurityRating: bez
Qto_DoorBaseQuantities - Height: 2.12 m; Width: 1 m; Area: 2.12 m2; Perimeter: 0 m

# IfcDoor: I.D021
In: Půdorys 1.PP
Type - PredefinedType: DOOR; ParameterTakesPrecedence: no
OverallHeight: 2.12 m; OverallWidth: 1 m
NEMSOK - Kód prvku: DD01.02.0021; Jednotková_cena: 0; V6: 0 m; V7: 0 m; V8: 0 m; V9: 0; Verze programu: 2.2; Označení: I.D021; Plugin_Bezeichnung: MainObject; Plugin_Objektname: SmartPartCompressed; Uvažované procento prosklení: 0; Verze: 4.0; Podlaží: 1.PP; šířka: 900; výška: 1970; Funkce (venkovní): Ne; Připojení EZS: Ne; Připojení NN: Ne; Připojení EPS: Ne; Připojení MaR: Ne; Připojení ACS: Ne; Typ dveřní zarážky: Plastová nástěnná; Typ samozavírače: Bez; Vzduchová neprůzvučnost: 32; Dveře_Světlá-šířka: 0 m; Dveře_Světlá-výška: 0 m; Zárubeň/Rám_Typ: pro zazdění; Zárubeň/Rám_Materiál: Ocelová; Zárubeň/Rám_Povrch: komaxit; Křídlo_Materiál: Dřevěné; Křídlo_Povrch_Int.: HPL laminát; Křídlo_Povrch_Ext.: HPL laminát; Kování_Klika_Int.: klika; Kování_Klika_Ext.: koule; Kování_Zámek: mechanický vložkový; Specifikace: Interiérové dveře jednokřídlé plné; Allright_Stavebni_dil_ID: 1364Obj0798521742; Jednotka: Kus; Název_objektu: Dveře - objekt+SmartPart; GlassSurface: 0.1; HeightWindowSillOutside: 0; HeightWindowSillInside: 0; OffsetOpeningBottom: 0; OffsetOpeningTop: 0; OffsetOpeningLeft: 0; OffsetOpeningRight: 0; DeductionOpeningBottom: 100; DeductionOpeningLeft: 50; DeductionOpeningRight: 50; DeductionOpeningTop: 50
Pset_DoorCommon - Status: NEW; IsExternal: no; ThermalTransmittance: 0 W/K/m2; AcousticRating: 32 dB; HandicapAccessible: no; SmokeStop: no; SelfClosing: no; FireExit: no; SecurityRating: bez
Qto_DoorBaseQuantities - Height: 2.12 m; Width: 1 m; Area: 2.12 m2; Perimeter: 0 m

# IfcDoor: I.D022
In: Půdorys 1.PP
Type - PredefinedType: DOOR; ParameterTakesPrecedence: no
OverallHeight: 2.12 m; OverallWidth: 1.2 m
NEMSOK - Kód prvku: DD01.02.0022; Jednotková_cena: 0; V6: 0 m; V7: 0 m; V8: 0 m; V9: 0; Verze programu: 2.2; Označení: I.D022; Plugin_Bezeichnung: MainObject; Plugin_Objektname: SmartPartCompressed; Uvažované procento prosklení: 0; Verze: 4.0; Podlaží: 1.PP; šířka: 1100; výška: 1970; Funkce (venkovní): Ne; Připojení EZS: Ne; Připojení NN: Ne; Připojení EPS: Ne; Připojení MaR: Ne; Připojení ACS: Ne; Typ dveřní zarážky: Plastová nástěnná; Typ samozavírače: Bez; Vzduchová neprůzvučnost: 0; Dveře_Světlá-šířka: 0 m; Dveře_Světlá-výška: 0 m; Zárubeň/Rám_Typ: dvoudílná vyztužená olověnou vystélkou; Zárubeň/Rám_Materiál: Ocelová; Zárubeň/Rám_Povrch: komaxit; Křídlo_Materiál: Dřevěné s mezivrstvou olověného plechu; Kování_Klika_Int.: klika; Kování_Klika_Ext.: koule; Kování_Zámek: mechanický vložkový; Specifikace: Interiérové dveře jednokřídlé plné; Allright_Stavebni_dil_ID: 1364Obj0000006171; Jednotka: Kus; Název_objektu: Dveře - objekt+SmartPart; GlassSurface: 0.12; HeightWindowSillOutside: 0; HeightWindowSillInside: 0; OffsetOpeningBottom: 0; OffsetOpeningTop: 0; OffsetOpeningLeft: 0; OffsetOpeningRight: 0; DeductionOpeningBottom: 100; DeductionOpeningLeft: 50; DeductionOpeningRight: 50; DeductionOpeningTop: 50
Pset_DoorCommon - Status: NEW; IsExternal: no; ThermalTransmittance: 0 W/K/m2; HandicapAccessible: no; SmokeStop: no; SelfClosing: no; FireExit: no; SecurityRating: bez
Qto_DoorBaseQuantities - Height: 2.12 m; Width: 1.2 m; Area: 2.544 m2; Perimeter: 0 m

# IfcDoor: I.D023
In: Půdorys 1.PP
Type - PredefinedType: DOOR; ParameterTakesPrecedence: no
OverallHeight: 2.12 m; OverallWidth: 1 m
NEMSOK - Kód prvku: DD01.02.0023; Jednotková_cena: 0; V6: 0 m; V7: 0 m; V8: 0 m; V9: 0; Verze programu: 2.2; Označení: I.D023; Plugin_Bezeichnung: MainObject; Plugin_Objektname: SmartPartCompressed; Uvažované procento prosklení: 0; Verze: 4.0; Podlaží: 1.PP; šířka: 900; výška: 1970; Funkce (venkovní): Ne; Připojení EZS: Ne; Připojení NN: Ne; Připojení EPS: Ne; Připojení MaR: Ne; Připojení ACS: Ne; Typ dveřní zarážky: Bez; Typ samozavírače: Bez; Vzduchová neprůzvučnost: 0; Dveře_Světlá-šířka: 0 m; Dveře_Světlá-výška: 0 m; Zárubeň/Rám_Typ: dvoudílná vyztužená olověnou vystélkou; Zárubeň/Rám_Materiál: Ocelová; Zárubeň/Rám_Povrch: komaxit; Křídlo_Materiál: Dřevěné s mezivrstvou olověného plechu; Kování_Klika_Int.: klika; Kování_Klika_Ext.: klika; Kování_Zámek: mechanický vložkový; Specifikace: Interiérové dveře jednokřídlé plné; Allright_Stavebni_dil_ID: 1364Obj0000004103; Jednotka: Kus; Název_objektu: Dveře - objekt+SmartPart; GlassSurface: 0.1; HeightWindowSillOutside: 0; HeightWindowSillInside: 0; OffsetOpeningBottom: 0; OffsetOpeningTop: 0; OffsetOpeningLeft: 0; OffsetOpeningRight: 0; DeductionOpeningBottom: 100; DeductionOpeningLeft: 50; DeductionOpeningRight: 50; DeductionOpeningTop: 50
Pset_DoorCommon - Status: NEW; IsExternal: no; ThermalTransmittance: 0 W/K/m2; HandicapAccessible: no; SmokeStop: no; SelfClosing: no; FireExit: no; SecurityRating: bez
Qto_DoorBaseQuantities - Height: 2.12 m; Width: 1 m; Area: 2.12 m2; Perimeter: 0 m

# IfcDoor: I.D024
In: Půdorys 1.PP
Type - PredefinedType: DOOR; ParameterTakesPrecedence: no
OverallHeight: 2.12 m; OverallWidth: 1 m
NEMSOK - Kód prvku: DD01.02.0024; Jednotková_cena: 0; V6: 0 m; V7: 0 m; V8: 0 m; V9: 0; Verze programu: 2.2; Označení: I.D024; Plugin_Bezeichnung: MainObject; Plugin_Objektname: SmartPartCompressed; Uvažované procento prosklení: 0; Verze: 4.0; Podlaží: 1.PP; šířka: 900; výška: 1970; Funkce (venkovní): Ne; Připojení EZS: Ne; Připojení NN: Ne; Připojení EPS: Ne; Připojení MaR: Ne; Připojení ACS: Ne; Typ dveřní zarážky: Plastová nástěnná; Typ samozavírače: Hřebenový s kluznou lištou; Vzduchová neprůzvučnost: 0; Dveře_Světlá-šířka: 0 m; Dveře_Světlá-výška: 0 m; Zárubeň/Rám_Typ: pro zazdění; Zárubeň/Rám_Materiál: Ocelová; Zárubeň/Rám_Povrch: komaxit; Křídlo_Materiál: Dřevěné; Křídlo_Povrch_Int.: HPL laminát; Křídlo_Povrch_Ext.: HPL laminát; Kování_Klika_Int.: klika; Kování_Klika_Ext.: klika; Kování_Zámek: mechanický vložkový; Specifikace: Interiérové dveře jednokřídlé prosklené; Allright_Stavebni_dil_ID: 1364Obj0798521875; Jednotka: Kus; Název_objektu: Dveře - objekt+SmartPart; GlassSurface: 1.1283; HeightWindowSillOutside: 0; HeightWindowSillInside: 0; OffsetOpeningBottom: 0; OffsetOpeningTop: 0; OffsetOpeningLeft: 0; OffsetOpeningRight: 0; DeductionOpeningBottom: 100; DeductionOpeningLeft: 50; DeductionOpeningRight: 50; DeductionOpeningTop: 50
Pset_DoorCommon - Status: NEW; IsExternal: no; ThermalTransmittance: 0 W/K/m2; HandicapAccessible: no; SmokeStop: no; SelfClosing: no; FireExit: no; SecurityRating: bez
Qto_DoorBaseQuantities - Height: 2.12 m; Width: 1 m; Area: 2.12 m2; Perimeter: 0 m

# IfcDoor: I.D025
In: Půdorys 1.PP
Type - PredefinedType: DOOR; ParameterTakesPrecedence: no
OverallHeight: 2.12 m; OverallWidth: 1.2 m
NEMSOK - Kód prvku: DD01.02.0025; Jednotková_cena: 0; V6: 0 m; V7: 0 m; V8: 0 m; V9: 0; Verze programu: 2.2; Označení: I.D025; Plugin_Bezeichnung: MainObject; Plugin_Objektname: SmartPartCompressed; Uvažované procento prosklení: 0; Verze: 4.0; Podlaží: 1.PP; šířka: 1100; výška: 1970; Funkce (venkovní): Ne; Připojení EZS: Ne; Připojení NN: Ne; Připojení EPS: Ne; Připojení MaR: Ne; Připojení ACS: Ne; Typ dveřní zarážky: Plastová nástěnná; Typ samozavírače: Bez; Vzduchová neprůzvučnost: 32; Dveře_Světlá-šířka: 0 m; Dveře_Světlá-výška: 0 m; Zárubeň/Rám_Typ: dvoudílná; Zárubeň/Rám_Materiál: Ocelová; Zárubeň/Rám_Povrch: komaxit; Křídlo_Materiál: Dřevěné; Křídlo_Povrch_Int.: HPL laminát; Křídlo_Povrch_Ext.: HPL laminát; Kování_Klika_Int.: klika; Kování_Klika_Ext.: koule; Kování_Zámek: mechanický vložkový; Specifikace: Interiérové dveře jednokřídlé plné; Allright_Stavebni_dil_ID: 1364Obj0000003943; Jednotka: Kus; Název_objektu: Dveře - objekt+SmartPart; GlassSurface: 0.12; HeightWindowSillOutside: 0; HeightWindowSillInside: 0; OffsetOpeningBottom: 0; OffsetOpeningTop: 0; OffsetOpeningLeft: 0; OffsetOpeningRight: 0; DeductionOpeningBottom: 100; DeductionOpeningLeft: 50; DeductionOpeningRight: 50; DeductionOpeningTop: 50
Pset_DoorCommon - Status: NEW; IsExternal: no; ThermalTransmittance: 0 W/K/m2; AcousticRating: 32 dB; HandicapAccessible: no; SmokeStop: no; SelfClosing: no; FireExit: no; SecurityRating: bez
Qto_DoorBaseQuantities - Height: 2.12 m; Width: 1.2 m; Area: 2.544 m2; Perimeter: 0 m

# IfcDoor: I.D026
In: Půdorys 1.PP
Type - PredefinedType: DOOR; ParameterTakesPrecedence: no
OverallHeight: 2.12 m; OverallWidth: 1 m
NEMSOK - Kód prvku: DD01.02.0026; Jednotková_cena: 0; V6: 0 m; V7: 0 m; V8: 0 m; V9: 0; Verze programu: 2.2; Označení: I.D026; Plugin_Bezeichnung: MainObject; Plugin_Objektname: SmartPartCompressed; Uvažované procento prosklení: 0; Verze: 4.0; Podlaží: 1.PP; šířka: 900; výška: 1970; Funkce (venkovní): Ne; Připojení EZS: Ne; Připojení NN: Ne; Připojení EPS: Ne; Připojení MaR: Ne; Připojení ACS: Ne; Typ dveřní zarážky: Bez; Typ samozavírače: Bez; Vzduchová neprůzvučnost: 32; Dveře_Světlá-šířka: 0 m; Dveře_Světlá-výška: 0 m; Zárubeň/Rám_Typ: dvoudílná; Zárubeň/Rám_Materiál: Ocelová; Zárubeň/Rám_Povrch: komaxit; Křídlo_Materiál: Dřevěné; Křídlo_Povrch_Int.: HPL laminát; Křídlo_Povrch_Ext.: HPL laminát; Kování_Klika_Int.: klika; Kování_Klika_Ext.: klika; Kování_Zámek: mechanický vložkový; Specifikace: Interiérové dveře jednokřídlé plné; Allright_Stavebni_dil_ID: 1364Obj0000003999; Jednotka: Kus; Název_objektu: Dveře - objekt+SmartPart; GlassSurface: 0.1; HeightWindowSillOutside: 0; HeightWindowSillInside: 0; OffsetOpeningBottom: 0; OffsetOpeningTop: 0; OffsetOpeningLeft: 0; OffsetOpeningRight: 0; DeductionOpeningBottom: 100; DeductionOpeningLeft: 50; DeductionOpeningRight: 50; DeductionOpeningTop: 50
Pset_DoorCommon - Status: NEW; IsExternal: no; ThermalTransmittance: 0 W/K/m2; AcousticRating: 32 dB; HandicapAccessible: no; SmokeStop: no; SelfClosing: no; FireExit: no; SecurityRating: bez
Qto_DoorBaseQuantities - Height: 2.12 m; Width: 1 m; Area: 2.12 m2; Perimeter: 0 m

# IfcDoor: I.D027
In: Půdorys 1.PP
Type - PredefinedType: DOOR; ParameterTakesPrecedence: no
OverallHeight: 2.12 m; OverallWidth: 1.2 m
NEMSOK - Kód prvku: DD01.02.0027; Jednotková_cena: 0; V6: 0 m; V7: 0 m; V8: 0 m; V9: 0; Verze programu: 2.2; Označení: I.D027; Plugin_Bezeichnung: MainObject; Plugin_Objektname: SmartPartCompressed; Uvažované procento prosklení: 0; Verze: 4.0; Podlaží: 1.PP; šířka: 1100; výška: 1970; Funkce (venkovní): Ne; Připojení EZS: Ne; Připojení NN: Ne; Připojení EPS: Ne; Připojení MaR: Ne; Připojení ACS: Ne; Typ dveřní zarážky: Plastová nástěnná; Typ samozavírače: Bez; Vzduchová neprůzvučnost: 32; Dveře_Světlá-šířka: 0 m; Dveře_Světlá-výška: 0 m; Zárubeň/Rám_Typ: dvoudílná; Zárubeň/Rám_Materiál: Ocelová; Zárubeň/Rám_Povrch: komaxit; Křídlo_Materiál: Dřevěné; Křídlo_Povrch_Int.: HPL laminát; Křídlo_Povrch_Ext.: HPL laminát; Kování_Klika_Int.: klika; Kování_Klika_Ext.: koule; Kování_Zámek: mechanický vložkový; Specifikace: Interiérové dveře jednokřídlé plné; Allright_Stavebni_dil_ID: 1364Obj0000006138; Jednotka: Kus; Název_objektu: Dveře - objekt+SmartPart; GlassSurface: 0.12; HeightWindowSillOutside: 0; HeightWindowSillInside: 0; OffsetOpeningBottom: 0; OffsetOpeningTop: 0; OffsetOpeningLeft: 0; OffsetOpeningRight: 0; DeductionOpeningBottom: 100; DeductionOpeningLeft: 50; DeductionOpeningRight: 50; DeductionOpeningTop: 50
Pset_DoorCommon - Status: NEW; IsExternal: no; ThermalTransmittance: 0 W/K/m2; AcousticRating: 32 dB; HandicapAccessible: no; SmokeStop: no; SelfClosing: no; FireExit: no; SecurityRating: bez
Qto_DoorBaseQuantities - Height: 2.12 m; Width: 1.2 m; Area: 2.544 m2; Perimeter: 0 m

# IfcDoor: I.D028
In: Půdorys 1.PP
Type - PredefinedType: DOOR; ParameterTakesPrecedence: no
OverallHeight: 2.12 m; OverallWidth: 1.2 m
NEMSOK - Kód prvku: DD01.02.0028; Jednotková_cena: 0; V6: 0 m; V7: 0 m; V8: 0 m; V9: 0; Verze programu: 2.2; Označení: I.D028; Plugin_Bezeichnung: MainObject; Plugin_Objektname: SmartPartCompressed; Uvažované procento prosklení: 100; Verze: 4.0; Podlaží: 1.PP; šířka: 1100; výška: 1970; Funkce (venkovní): Ne; Připojení EZS: Ne; Připojení NN: Ne; Připojení EPS: Ne; Připojení MaR: Ne; Připojení ACS: Ne; Typ dveřní zarážky: Plastová nástěnná; Typ samozavírače: Hřebenový s kluznou lištou; Vzduchová neprůzvučnost: 0; Dveře_Světlá-šířka: 0 m; Dveře_Světlá-výška: 0 m; Zárubeň/Rám_Typ: pro zazdění; Zárubeň/Rám_Materiál: Ocelová; Zárubeň/Rám_Povrch: komaxit; Křídlo_Materiál: Dřevěné; Křídlo_Povrch_Int.: HPL laminát; Křídlo_Povrch_Ext.: HPL laminát; Kování_Klika_Int.: klika; Kování_Klika_Ext.: klika; Kování_Zámek: mechanický vložkový; Specifikace: Interiérové dveře jednokřídlé prosklené; Allright_Stavebni_dil_ID: 1364Obj0798529229; Jednotka: Kus; Název_objektu: Dveře - objekt+SmartPart; GlassSurface: 1.4421; HeightWindowSillOutside: 0; HeightWindowSillInside: 0; OffsetOpeningBottom: 0; OffsetOpeningTop: 0; OffsetOpeningLeft: 0; OffsetOpeningRight: 0; DeductionOpeningBottom: 100; DeductionOpeningLeft: 50; DeductionOpeningRight: 50; DeductionOpeningTop: 50
Pset_DoorCommon - Status: NEW; IsExternal: no; ThermalTransmittance: 0 W/K/m2; HandicapAccessible: no; SmokeStop: no; SelfClosing: no; FireExit: no; SecurityRating: bez
Qto_DoorBaseQuantities - Height: 2.12 m; Width: 1.2 m; Area: 2.544 m2; Perimeter: 0 m

# IfcDoor: I.D029
In: Půdorys 1.PP
Type - PredefinedType: DOOR; ParameterTakesPrecedence: no
OverallHeight: 2.12 m; OverallWidth: 0.9 m
NEMSOK - Kód prvku: DD01.02.0029; Jednotková_cena: 0; V6: 0 m; V7: 0 m; V8: 0 m; V9: 0; Verze programu: 2.2; Označení: I.D029; Plugin_Bezeichnung: MainObject; Plugin_Objektname: SmartPartCompressed; Uvažované procento prosklení: 0; Verze: 4.0; Podlaží: 1.PP; šířka: 800; výška: 1970; Funkce (venkovní): Ne; Připojení EZS: Ne; Připojení NN: Ne; Připojení EPS: Ne; Připojení MaR: Ne; Připojení ACS: Ne; Typ dveřní zarážky: Bez; Typ samozavírače: Hřebenový s kluznou lištou; Vzduchová neprůzvučnost: 0; Dveře_Světlá-šířka: 0 m; Dveře_Světlá-výška: 0 m; Zárubeň/Rám_Typ: pro zazdění; Zárubeň/Rám_Materiál: Ocelová; Zárubeň/Rám_Povrch: komaxit; Křídlo_Materiál: Dřevěné; Křídlo_Povrch_Int.: HPL laminát; Křídlo_Povrch_Ext.: HPL laminát; Kování_Klika_Int.: klika; Kování_Klika_Ext.: koule; Kování_Zámek: mechanický vložkový; Specifikace: Interiérové dveře jednokřídlé plné; Allright_Stavebni_dil_ID: 1364Obj0798528553; Jednotka: Kus; Název_objektu: Dveře - objekt+SmartPart; GlassSurface: 0.09; HeightWindowSillOutside: 0; HeightWindowSillInside: 0; OffsetOpeningBottom: 0; OffsetOpeningTop: 0; OffsetOpeningLeft: 0; OffsetOpeningRight: 0; DeductionOpeningBottom: 100; DeductionOpeningLeft: 50; DeductionOpeningRight: 50; DeductionOpeningTop: 50
Pset_DoorCommon - Status: NEW; IsExternal: no; ThermalTransmittance: 0 W/K/m2; HandicapAccessible: no; SmokeStop: no; SelfClosing: no; FireExit: no; SecurityRating: bez
Qto_DoorBaseQuantities - Height: 2.12 m; Width: 0.9 m; Area: 1.908 m2; Perimeter: 0 m

# IfcDoor: I.D030
In: Půdorys 1.PP
Type - PredefinedType: DOOR; ParameterTakesPrecedence: no
OverallHeight: 2.12 m; OverallWidth: 1 m
NEMSOK - Kód prvku: DD01.02.0030; Jednotková_cena: 0; V6: 0 m; V7: 0 m; V8: 0 m; V9: 0; Verze programu: 2.2; Označení: I.D030; Plugin_Bezeichnung: MainObject; Plugin_Objektname: SmartPartCompressed; Uvažované procento prosklení: 0; Verze: 4.0; Podlaží: 1.PP; šířka: 900; výška: 1970; Funkce (venkovní): Ne; Připojení EZS: Ne; Připojení NN: Ne; Připojení EPS: Ne; Připojení MaR: Ne; Připojení ACS: Ne; Typ dveřní zarážky: Bez; Typ samozavírače: Bez; Vzduchová neprůzvučnost: 0; Dveře_Světlá-šířka: 0 m; Dveře_Světlá-výška: 0 m; Zárubeň/Rám_Typ: dvoudílná; Zárubeň/Rám_Materiál: Ocelová; Zárubeň/Rám_Povrch: komaxit; Křídlo_Materiál: Dřevěné; Křídlo_Povrch_Int.: HPL laminát; Křídlo_Povrch_Ext.: HPL laminát; Kování_Klika_Int.: klika; Kování_Klika_Ext.: koule; Kování_Zámek: mechanický vložkový; Specifikace: Interiérové dveře jednokřídlé plné; Allright_Stavebni_dil_ID: 1364Obj0798473681; Jednotka: Kus; Název_objektu: Dveře - objekt+SmartPart; GlassSurface: 0.1; HeightWindowSillOutside: 0; HeightWindowSillInside: 0; OffsetOpeningBottom: 0; OffsetOpeningTop: 0; OffsetOpeningLeft: 0; OffsetOpeningRight: 0; DeductionOpeningBottom: 100; DeductionOpeningLeft: 50; DeductionOpeningRight: 50; DeductionOpeningTop: 50
Pset_DoorCommon - Status: NEW; IsExternal: no; ThermalTransmittance: 0 W/K/m2; HandicapAccessible: no; SmokeStop: no; SelfClosing: no; FireExit: no; SecurityRating: bez
Qto_DoorBaseQuantities - Height: 2.12 m; Width: 1 m; Area: 2.12 m2; Perimeter: 0 m

# IfcDoor: I.D031
In: Půdorys 1.PP
Type - PredefinedType: DOOR; ParameterTakesPrecedence: no
OverallHeight: 2.12 m; OverallWidth: 1.2 m
NEMSOK - Kód prvku: DD01.02.0031; Jednotková_cena: 0; V6: 0 m; V7: 0 m; V8: 0 m; V9: 0; Verze programu: 2.2; Označení: I.D031; Plugin_Bezeichnung: MainObject; Plugin_Objektname: SmartPartCompressed; Uvažované procento prosklení: 0; Verze: 4.0; Podlaží: 1.PP; šířka: 1100; výška: 1970; Funkce (venkovní): Ne; Připojení EZS: Ne; Připojení NN: Ne; Připojení EPS: Ne; Připojení MaR: Ne; Připojení ACS: Ne; Typ dveřní zarážky: Bez; Typ samozavírače: Bez; Vzduchová neprůzvučnost: 0; Dveře_Světlá-šířka: 0 m; Dveře_Světlá-výška: 0 m; Zárubeň/Rám_Typ: dvoudílná; Zárubeň/Rám_Materiál: Ocelová; Zárubeň/Rám_Povrch: komaxit; Křídlo_Materiál: Dřevěné; Křídlo_Povrch_Int.: HPL laminát; Křídlo_Povrch_Ext.: HPL laminát; Kování_Klika_Int.: klika; Kování_Klika_Ext.: koule; Kování_Zámek: mechanický vložkový; Specifikace: Interiérové dveře jednokřídlé plné; Allright_Stavebni_dil_ID: 1364Obj0798606552; Jednotka: Kus; Název_objektu: Dveře - objekt+SmartPart; GlassSurface: 0.12; HeightWindowSillOutside: 0; HeightWindowSillInside: 0; OffsetOpeningBottom: 0; OffsetOpeningTop: 0; OffsetOpeningLeft: 0; OffsetOpeningRight: 0; DeductionOpeningBottom: 100; DeductionOpeningLeft: 50; DeductionOpeningRight: 50; DeductionOpeningTop: 50
Pset_DoorCommon - Status: NEW; IsExternal: no; ThermalTransmittance: 0 W/K/m2; HandicapAccessible: no; SmokeStop: no; SelfClosing: no; FireExit: no; SecurityRating: bez
Qto_DoorBaseQuantities - Height: 2.12 m; Width: 1.2 m; Area: 2.544 m2; Perimeter: 0 m

# IfcDoor: I.D032
In: Půdorys 1.PP
Type - PredefinedType: DOOR; ParameterTakesPrecedence: no
OverallHeight: 2.12 m; OverallWidth: 0.8 m
NEMSOK - Kód prvku: DD01.02.0032; Jednotková_cena: 0; V6: 0 m; V7: 0 m; V8: 0 m; V9: 0; Verze programu: 2.2; Označení: I.D032; Plugin_Bezeichnung: MainObject; Plugin_Objektname: SmartPartCompressed; Uvažované procento prosklení: 0; Verze: 4.0; Podlaží: 1.PP; šířka: 700; výška: 1970; Funkce (venkovní): Ne; Připojení EZS: Ne; Připojení NN: Ne; Připojení EPS: Ne; Připojení MaR: Ne; Připojení ACS: Ne; Typ dveřní zarážky: Bez; Typ samozavírače: Hřebenový s kluznou lištou; Vzduchová neprůzvučnost: 0; Dveře_Světlá-šířka: 0 m; Dveře_Světlá-výška: 0 m; Zárubeň/Rám_Typ: pro zazdění; Zárubeň/Rám_Materiál: Ocelová; Zárubeň/Rám_Povrch: komaxit; Křídlo_Materiál: Dřevěné; Křídlo_Povrch_Int.: HPL laminát; Křídlo_Povrch_Ext.: HPL laminát; Kování_Klika_Int.: klika; Kování_Klika_Ext.: koule; Kování_Zámek: mechanický vložkový; Specifikace: Interiérové dveře jednokřídlé plné; Allright_Stavebni_dil_ID: 1364Obj0798606525; Jednotka: Kus; Název_objektu: Dveře - objekt+SmartPart; GlassSurface: 0.08; HeightWindowSillOutside: 0; HeightWindowSillInside: 0; OffsetOpeningBottom: 0; OffsetOpeningTop: 0; OffsetOpeningLeft: 0; OffsetOpeningRight: 0; DeductionOpeningBottom: 100; DeductionOpeningLeft: 50; DeductionOpeningRight: 50; DeductionOpeningTop: 50
Pset_DoorCommon - Status: NEW; IsExternal: no; ThermalTransmittance: 0 W/K/m2; HandicapAccessible: no; SmokeStop: no; SelfClosing: yes; FireExit: no; SecurityRating: bez
Qto_DoorBaseQuantities - Height: 2.12 m; Width: 0.8 m; Area: 1.696 m2; Perimeter: 0 m

# IfcDoor: I.D033
In: Půdorys 1.PP
Type - PredefinedType: DOOR; ParameterTakesPrecedence: no
OverallHeight: 2.12 m; OverallWidth: 0.8 m
NEMSOK - Kód prvku: DD01.02.0033; Jednotková_cena: 0; V6: 0 m; V7: 0 m; V8: 0 m; V9: 0; Verze programu: 2.2; Označení: I.D033; Plugin_Bezeichnung: MainObject; Plugin_Objektname: SmartPartCompressed; Uvažované procento prosklení: 0; Verze: 4.0; Podlaží: 1.PP; šířka: 700; výška: 1970; Funkce (venkovní): Ne; Připojení EZS: Ne; Připojení NN: Ne; Připojení EPS: Ne; Připojení MaR: Ne; Připojení ACS: Ne; Typ dveřní zarážky: Plastová nástěnná; Typ samozavírače: Bez; Vzduchová neprůzvučnost: 0; Dveře_Světlá-šířka: 0 m; Dveře_Světlá-výška: 0 m; Zárubeň/Rám_Typ: dvoudílná; Zárubeň/Rám_Materiál: Ocelová; Zárubeň/Rám_Povrch: komaxit; Křídlo_Materiál: Dřevěné; Křídlo_Povrch_Int.: HPL laminát; Křídlo_Povrch_Ext.: HPL laminát; Kování_Klika_Int.: klika; Kování_Klika_Ext.: klika; Kování_Zámek: WC zámek; Specifikace: Interiérové dveře jednokřídlé plné; Allright_Stavebni_dil_ID: 1364Obj0000003612; Jednotka: Kus; Název_objektu: Dveře - objekt+SmartPart; GlassSurface: 0.08; HeightWindowSillOutside: 0; HeightWindowSillInside: 0; OffsetOpeningBottom: 0; OffsetOpeningTop: 0; OffsetOpeningLeft: 0; OffsetOpeningRight: 0; DeductionOpeningBottom: 100; DeductionOpeningLeft: 50; DeductionOpeningRight: 50; DeductionOpeningTop: 50
Pset_DoorCommon - Status: NEW; IsExternal: no; ThermalTransmittance: 0 W/K/m2; HandicapAccessible: no; SmokeStop: no; SelfClosing: no; FireExit: no; SecurityRating: bez
Qto_DoorBaseQuantities - Height: 2.12 m; Width: 0.8 m; Area: 1.696 m2; Perimeter: 0 m

# IfcDoor: I.D034
In: Půdorys 1.PP
Type - PredefinedType: DOOR; ParameterTakesPrecedence: no
OverallHeight: 2.02 m; OverallWidth: 0.9 m
NEMSOK - Kód prvku: DD01.02.0034; Jednotková_cena: 0; V6: 0 m; V7: 0 m; V8: 0 m; V9: 0; Verze programu: 2.2; Označení: I.D034; Plugin_Bezeichnung: MainObject; Plugin_Objektname: SmartPartCompressed; Uvažované procento prosklení: 0; Verze: 4.0; Podlaží: 1.PP; šířka: 800; výška: 1970; Funkce (venkovní): Ne; Připojení EZS: Ne; Připojení NN: Ne; Připojení EPS: Ne; Připojení MaR: Ne; Připojení ACS: Ne; Typ dveřní zarážky: Plastová nástěnná; Typ samozavírače: Hřebenový s kluznou lištou; Vzduchová neprůzvučnost: 37; Dveře_Světlá-šířka: 0 m; Dveře_Světlá-výška: 0 m; Zárubeň/Rám_Typ: dvoudílná; Zárubeň/Rám_Materiál: Ocelová; Zárubeň/Rám_Povrch: komaxit; Křídlo_Materiál: Dřevěné; Křídlo_Povrch_Int.: HPL laminát; Křídlo_Povrch_Ext.: HPL laminát; Kování_Klika_Int.: klika; Kování_Klika_Ext.: koule; Kování_Zámek: mechanický vložkový; Specifikace: Interiérové dveře jednokřídlé plné; Allright_Stavebni_dil_ID: 1364Obj0798606136; Jednotka: Kus; Název_objektu: Dveře - objekt+SmartPart; GlassSurface: 0; HeightWindowSillOutside: 0; HeightWindowSillInside: 0; OffsetOpeningBottom: 0; OffsetOpeningTop: 0; OffsetOpeningLeft: 0; OffsetOpeningRight: 0; DeductionOpeningBottom: 0; DeductionOpeningLeft: 50; DeductionOpeningRight: 50; DeductionOpeningTop: 50
Pset_DoorCommon - Status: NEW; IsExternal: no; FireRating: EW 30DP3-C; ThermalTransmittance: 0 W/K/m2; AcousticRating: 37 dB; HandicapAccessible: no; SmokeStop: no; SelfClosing: no; FireExit: no; SecurityRating: bez
Qto_DoorBaseQuantities - Height: 2.02 m; Width: 0.9 m; Area: 1.818 m2; Perimeter: 0 m

# IfcDoor: I.D035
In: Půdorys 1.PP
Type - PredefinedType: DOOR; ParameterTakesPrecedence: no
OverallHeight: 2.02 m; OverallWidth: 1.2 m
NEMSOK - Kód prvku: DD01.02.0035; Jednotková_cena: 0; V6: 0 m; V7: 0 m; V8: 0 m; V9: 0; Verze programu: 2.2; Označení: I.D035; Plugin_Bezeichnung: MainObject; Plugin_Objektname: SmartPartCompressed; Uvažované procento prosklení: 0; Verze: 4.0; Podlaží: 1.PP; šířka: 1200; výška: 1970; Funkce (venkovní): Ne; Připojení EZS: Ne; Připojení NN: Ne; Připojení EPS: Ne; Připojení MaR: Ne; Připojení ACS: Ne; Typ dveřní zarážky: Bez; Typ samozavírače: Hřebenový s kluznou lištou + koordinátor; Vzduchová neprůzvučnost: 0; Dveře_Světlá-šířka: 0.8 m; Dveře_Světlá-výška: 0 m; Zárubeň/Rám_Typ: dvoudílná; Zárubeň/Rám_Materiál: Ocelová; Zárubeň/Rám_Povrch: komaxit; Křídlo_Materiál: Dřevěné; Křídlo_Povrch_Int.: HPL laminát; Křídlo_Povrch_Ext.: HPL laminát; Kování_Klika_Int.: klika; Kování_Klika_Ext.: paniková klika; Kování_Zámek: mechanický vložkový; Specifikace: Interiérové dveře dvoukřídlé plné; Allright_Stavebni_dil_ID: 1364Obj0798606386; Jednotka: Kus; Název_objektu: Dveře - objekt+SmartPart; GlassSurface: 0; HeightWindowSillOutside: 0; HeightWindowSillInside: 0; OffsetOpeningBottom: 0; OffsetOpeningTop: 0; OffsetOpeningLeft: 0; OffsetOpeningRight: 0; DeductionOpeningBottom: 0; DeductionOpeningLeft: 50; DeductionOpeningRight: 50; DeductionOpeningTop: 50
Pset_DoorCommon - Status: NEW; IsExternal: no; FireRating: EW 30DP3-C; ThermalTransmittance: 0 W/K/m2; HandicapAccessible: no; SmokeStop: no; SelfClosing: no; FireExit: no; SecurityRating: bez
Qto_DoorBaseQuantities - Height: 2.02 m; Width: 1.2 m; Area: 2.424 m2; Perimeter: 0 m

# IfcDoor: I.D036
In: Půdorys 1.PP
Type - PredefinedType: DOOR; ParameterTakesPrecedence: no
OverallHeight: 2.12 m; OverallWidth: 1 m
NEMSOK - Kód prvku: DD01.02.0036; Jednotková_cena: 0; V6: 0 m; V7: 0 m; V8: 0 m; V9: 0; Verze programu: 2.2; Označení: I.D036; Plugin_Bezeichnung: MainObject; Plugin_Objektname: SmartPartCompressed; Uvažované procento prosklení: 0; Verze: 4.0; Podlaží: 1.PP; šířka: 900; výška: 1970; Funkce (venkovní): Ne; Připojení EZS: Ne; Připojení NN: Ne; Připojení EPS: Ne; Připojení MaR: Ne; Připojení ACS: Ne; Typ dveřní zarážky: Bez; Typ samozavírače: Hřebenový s kluznou lištou; Vzduchová neprůzvučnost: 0; Dveře_Světlá-šířka: 0 m; Dveře_Světlá-výška: 0 m; Zárubeň/Rám_Typ: dvoudílná; Zárubeň/Rám_Materiál: Ocelová; Zárubeň/Rám_Povrch: komaxit; Křídlo_Materiál: Dřevěné; Křídlo_Povrch_Int.: HPL laminát; Křídlo_Povrch_Ext.: HPL laminát; Kování_Klika_Int.: klika; Kování_Klika_Ext.: klika; Kování_Zámek: mechanický vložkový; Specifikace: Interiérové dveře jednokřídlé plné; Allright_Stavebni_dil_ID: 1364Obj0798605995; Jednotka: Kus; Název_objektu: Dveře - objekt+SmartPart; GlassSurface: 0.1; HeightWindowSillOutside: 0; HeightWindowSillInside: 0; OffsetOpeningBottom: 0; OffsetOpeningTop: 0; OffsetOpeningLeft: 0; OffsetOpeningRight: 0; DeductionOpeningBottom: 100; DeductionOpeningLeft: 50; DeductionOpeningRight: 50; DeductionOpeningTop: 50
Pset_DoorCommon - Status: NEW; IsExternal: no; FireRating: EW 30DP3-C; ThermalTransmittance: 0 W/K/m2; HandicapAccessible: no; SmokeStop: no; SelfClosing: no; FireExit: no; SecurityRating: bez
Qto_DoorBaseQuantities - Height: 2.12 m; Width: 1 m; Area: 2.12 m2; Perimeter: 0 m

# IfcDoor: I.D037
In: Půdorys 1.PP
Type - PredefinedType: DOOR; ParameterTakesPrecedence: no
OverallHeight: 2.32 m; OverallWidth: 1.9 m
NEMSOK - Kód prvku: DD01.02.0037; Jednotková_cena: 0; V6: 0 m; V7: 0 m; V8: 0 m; V9: 0; Verze programu: 2.2; Označení: I.D037; Plugin_Bezeichnung: MainObject; Plugin_Objektname: SmartPartCompressed; Uvažované procento prosklení: 0; Verze: 4.0; Podlaží: 1.PP; šířka: 1800; výška: 1970; Funkce (venkovní): Ne; Připojení EZS: Ne; Připojení NN: Ne; Připojení EPS: Ne; Připojení MaR: Ne; Připojení ACS: Ne; Typ dveřní zarážky: Bez; Typ samozavírače: Hřebenový s kluznou lištou; Vzduchová neprůzvučnost: 37; Dveře_Světlá-šířka: 0 m; Dveře_Světlá-výška: 0 m; Zárubeň/Rám_Typ: dvoudílná; Zárubeň/Rám_Materiál: Ocelová; Zárubeň/Rám_Povrch: komaxit; Křídlo_Materiál: Dřevěné; Křídlo_Povrch_Int.: HPL laminát; Křídlo_Povrch_Ext.: HPL laminát; Kování_Klika_Int.: klika; Kování_Klika_Ext.: koule; Kování_Zámek: mechanický vložkový; Specifikace: Interiérové dveře dvoukřídlé plné; Allright_Stavebni_dil_ID: 1364Obj0798498443; Jednotka: Kus; Název_objektu: Dveře - objekt+SmartPart; GlassSurface: 0; HeightWindowSillOutside: 0; HeightWindowSillInside: 0; OffsetOpeningBottom: 0; OffsetOpeningTop: 0; OffsetOpeningLeft: 0; OffsetOpeningRight: 0; DeductionOpeningBottom: 300; DeductionOpeningLeft: 50; DeductionOpeningRight: 50; DeductionOpeningTop: 50
Pset_DoorCommon - Status: NEW; IsExternal: no; FireRating: EW 30DP3-C; ThermalTransmittance: 0 W/K/m2; AcousticRating: 37 dB; HandicapAccessible: no; SmokeStop: no; SelfClosing: no; FireExit: no; SecurityRating: bez
Qto_DoorBaseQuantities - Height: 2.32 m; Width: 1.9 m; Area: 4.408 m2; Perimeter: 0 m

# IfcDoor: I.D038
In: Půdorys 1.PP
Type - PredefinedType: DOOR; ParameterTakesPrecedence: no
OverallHeight: 2.32 m; OverallWidth: 1 m
NEMSOK - Kód prvku: DD01.02.0038; Jednotková_cena: 0; V6: 0 m; V7: 0 m; V8: 0 m; V9: 0; Verze programu: 2.2; Označení: I.D038; Plugin_Bezeichnung: MainObject; Plugin_Objektname: SmartPartCompressed; Uvažované procento prosklení: 100; Verze: 4.0; Podlaží: 1.PP; šířka: 900; výška: 1970; Funkce (venkovní): Ne; Připojení EZS: Ne; Připojení NN: Ne; Připojení EPS: Ne; Připojení MaR: Ne; Připojení ACS: Ne; Typ dveřní zarážky: Plastová nástěnná; Typ samozavírače: Bez; Vzduchová neprůzvučnost: 0; Dveře_Světlá-šířka: 0 m; Dveře_Světlá-výška: 0 m; Zárubeň/Rám_Typ: dvoudílná; Zárubeň/Rám_Materiál: Ocelová; Zárubeň/Rám_Povrch: komaxit; Křídlo_Materiál: Dřevěné; Křídlo_Povrch_Int.: HPL laminát; Křídlo_Povrch_Ext.: HPL laminát; Kování_Klika_Int.: klika; Kování_Klika_Ext.: klika; Kování_Zámek: mechanický vložkový; Specifikace: Interiérové dveře jednokřídlé prosklené; Allright_Stavebni_dil_ID: 1364Obj0798495660; Jednotka: Kus; Název_objektu: Dveře - objekt+SmartPart; GlassSurface: 1.5383; HeightWindowSillOutside: 0; HeightWindowSillInside: 0; OffsetOpeningBottom: 0; OffsetOpeningTop: 0; OffsetOpeningLeft: 0; OffsetOpeningRight: 0; DeductionOpeningBottom: 300; DeductionOpeningLeft: 50; DeductionOpeningRight: 50; DeductionOpeningTop: 50
Pset_DoorCommon - Status: NEW; IsExternal: no; ThermalTransmittance: 0 W/K/m2; HandicapAccessible: no; SmokeStop: no; SelfClosing: no; FireExit: no; SecurityRating: bez
Qto_DoorBaseQuantities - Height: 2.32 m; Width: 1 m; Area: 2.32 m2; Perimeter: 0 m

# IfcDoor: I.D039
In: Půdorys 1.PP
Type - PredefinedType: DOOR; ParameterTakesPrecedence: no
OverallHeight: 2.32 m; OverallWidth: 1 m
NEMSOK - Kód prvku: DD01.02.0039; Jednotková_cena: 0; V6: 0 m; V7: 0 m; V8: 0 m; V9: 0; Verze programu: 2.2; Označení: I.D039; Plugin_Bezeichnung: MainObject; Plugin_Objektname: SmartPartCompressed; Uvažované procento prosklení: 100; Verze: 4.0; Podlaží: 1.PP; šířka: 900; výška: 1970; Funkce (venkovní): Ne; Připojení EZS: Ne; Připojení NN: Ne; Připojení EPS: Ne; Připojení MaR: Ne; Připojení ACS: Ne; Typ dveřní zarážky: Plastová nástěnná; Typ samozavírače: Bez; Vzduchová neprůzvučnost: 32; Dveře_Světlá-šířka: 0 m; Dveře_Světlá-výška: 0 m; Zárubeň/Rám_Typ: dvoudílná; Zárubeň/Rám_Materiál: Ocelová; Zárubeň/Rám_Povrch: komaxit; Křídlo_Materiál: Dřevěné; Křídlo_Povrch_Int.: HPL laminát; Křídlo_Povrch_Ext.: HPL laminát; Kování_Klika_Int.: klika; Kování_Klika_Ext.: koule; Kování_Zámek: mechanický vložkový; Specifikace: Interiérové dveře jednokřídlé prosklené; Allright_Stavebni_dil_ID: 1364Obj0798495725; Jednotka: Kus; Název_objektu: Dveře - objekt+SmartPart; GlassSurface: 1.5383; HeightWindowSillOutside: 0; HeightWindowSillInside: 0; OffsetOpeningBottom: 0; OffsetOpeningTop: 0; OffsetOpeningLeft: 0; OffsetOpeningRight: 0; DeductionOpeningBottom: 300; DeductionOpeningLeft: 50; DeductionOpeningRight: 50; DeductionOpeningTop: 50
Pset_DoorCommon - Status: NEW; IsExternal: no; ThermalTransmittance: 0 W/K/m2; AcousticRating: 32 dB; HandicapAccessible: no; SmokeStop: no; SelfClosing: no; FireExit: no; SecurityRating: bez
Qto_DoorBaseQuantities - Height: 2.32 m; Width: 1 m; Area: 2.32 m2; Perimeter: 0 m

# IfcDoor: I.D040
In: Půdorys 1.PP
Type - PredefinedType: DOOR; ParameterTakesPrecedence: no
OverallHeight: 2.32 m; OverallWidth: 1 m
NEMSOK - Kód prvku: DD01.02.0040; Jednotková_cena: 0; V6: 0 m; V7: 0 m; V8: 0 m; V9: 0; Verze programu: 2.2; Označení: I.D040; Plugin_Bezeichnung: MainObject; Plugin_Objektname: SmartPartCompressed; Uvažované procento prosklení: 0; Verze: 4.0; Podlaží: 1.PP; šířka: 900; výška: 1970; Funkce (venkovní): Ne; Připojení EZS: Ne; Připojení NN: Ne; Připojení EPS: Ne; Připojení MaR: Ne; Připojení ACS: Ne; Typ dveřní zarážky: Plastová nástěnná; Typ samozavírače: Hřebenový s kluznou lištou; Vzduchová neprůzvučnost: 0; Dveře_Světlá-šířka: 0 m; Dveře_Světlá-výška: 0 m; Zárubeň/Rám_Typ: dvoudílná; Zárubeň/Rám_Materiál: Ocelová; Zárubeň/Rám_Povrch: komaxit; Křídlo_Materiál: Dřevěné; Křídlo_Povrch_Int.: HPL laminát; Křídlo_Povrch_Ext.: HPL laminát; Kování_Klika_Int.: klika; Kování_Klika_Ext.: koule; Kování_Zámek: mechanický vložkový; Specifikace: Interiérové dveře jednokřídlé plné; Allright_Stavebni_dil_ID: 1364Obj0798498715; Jednotka: Kus; Název_objektu: Dveře - objekt+SmartPart; GlassSurface: 0.3; HeightWindowSillOutside: 0; HeightWindowSillInside: 0; OffsetOpeningBottom: 0; OffsetOpeningTop: 0; OffsetOpeningLeft: 0; OffsetOpeningRight: 0; DeductionOpeningBottom: 300; DeductionOpeningLeft: 50; DeductionOpeningRight: 50; DeductionOpeningTop: 50
Pset_DoorCommon - Status: NEW; IsExternal: no; ThermalTransmittance: 0 W/K/m2; HandicapAccessible: no; SmokeStop: no; SelfClosing: no; FireExit: no; SecurityRating: bez
Qto_DoorBaseQuantities - Height: 2.32 m; Width: 1 m; Area: 2.32 m2; Perimeter: 0 m

# IfcDoor: I.D041
In: Půdorys 1.PP
Type - PredefinedType: DOOR; ParameterTakesPrecedence: no
OverallHeight: 2.02 m; OverallWidth: 1.2 m
NEMSOK - Kód prvku: DD01.02.0041; Jednotková_cena: 0; V6: 0 m; V7: 0 m; V8: 0 m; V9: 0; Verze programu: 2.2; Označení: I.D041; Plugin_Bezeichnung: MainObject; Plugin_Objektname: SmartPartCompressed; Uvažované procento prosklení: 0; Verze: 4.0; Podlaží: 1.PP; šířka: 1100; výška: 1970; Funkce (venkovní): Ne; Připojení EZS: Ne; Připojení NN: Ne; Připojení EPS: Ne; Připojení MaR: Ne; Připojení ACS: Ne; Typ dveřní zarážky: Bez; Typ samozavírače: Hřebenový s kluznou lištou; Vzduchová neprůzvučnost: 37; Dveře_Světlá-šířka: 0 m; Dveře_Světlá-výška: 0 m; Zárubeň/Rám_Typ: dvoudílná; Zárubeň/Rám_Materiál: Ocelová; Zárubeň/Rám_Povrch: komaxit; Křídlo_Materiál: Dřevěné; Křídlo_Povrch_Int.: HPL laminát; Křídlo_Povrch_Ext.: HPL laminát; Kování_Klika_Int.: klika; Kování_Klika_Ext.: koule; Kování_Zámek: mechanický vložkový; Specifikace: Interiérové dveře jednokřídlé plné; Allright_Stavebni_dil_ID: 1364Obj0798606478; Jednotka: Kus; Název_objektu: Dveře - objekt+SmartPart; GlassSurface: 0; HeightWindowSillOutside: 0; HeightWindowSillInside: 0; OffsetOpeningBottom: 0; OffsetOpeningTop: 0; OffsetOpeningLeft: 0; OffsetOpeningRight: 0; DeductionOpeningBottom: 0; DeductionOpeningLeft: 50; DeductionOpeningRight: 50; DeductionOpeningTop: 50
Pset_DoorCommon - Status: NEW; IsExternal: no; FireRating: EI 30DP3-Sm-C; ThermalTransmittance: 0 W/K/m2; AcousticRating: 37 dB; HandicapAccessible: no; SmokeStop: no; SelfClosing: no; FireExit: no; SecurityRating: bez
Qto_DoorBaseQuantities - Height: 2.02 m; Width: 1.2 m; Area: 2.424 m2; Perimeter: 0 m

# IfcDoor: I.D101
In: Půdorys 1.NP
Type - PredefinedType: DOOR; ParameterTakesPrecedence: no
OverallHeight: 2.45 m; OverallWidth: 0.9 m
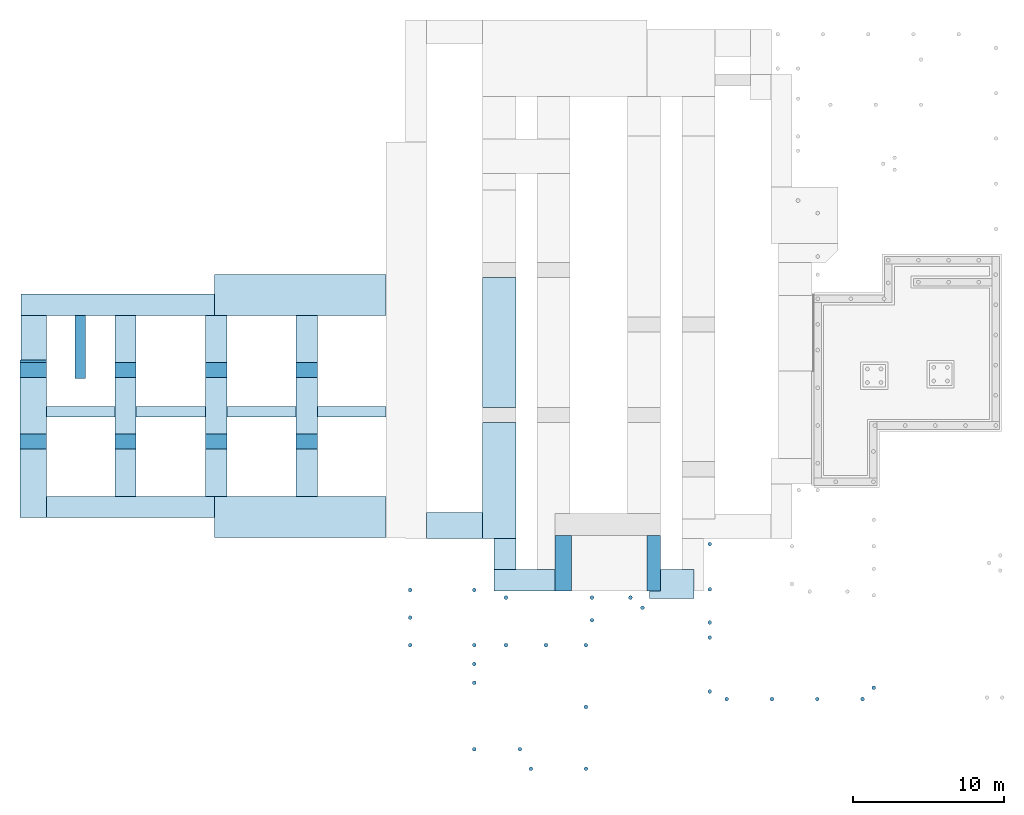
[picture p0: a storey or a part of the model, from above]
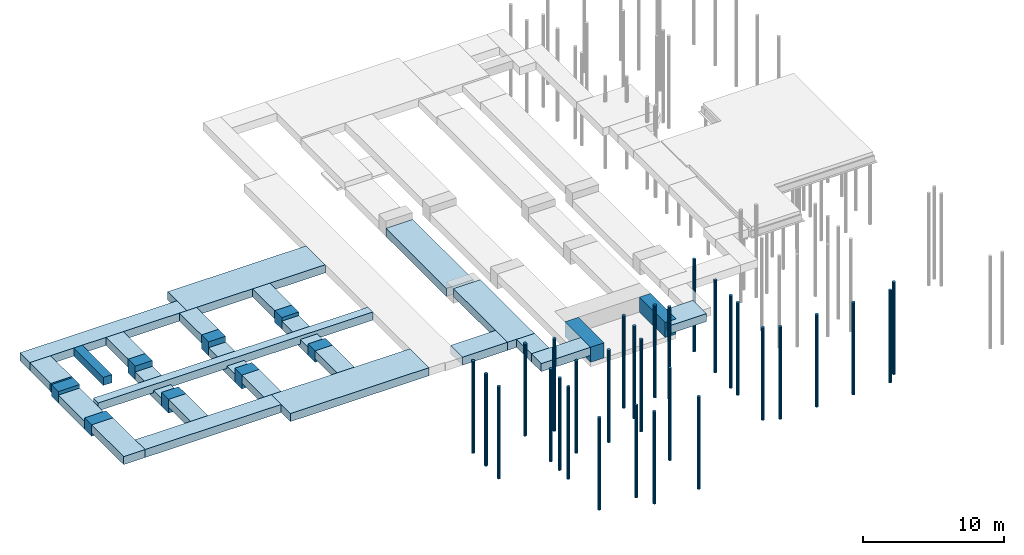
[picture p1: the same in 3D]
Properties of the parts of a building model (IFC4), part 10 of 45

# IfcDoor: I.D101
NEMSOK - Kód prvku: DD01.03.0101; Jednotková_cena: 0; V6: 0 m; V7: 0 m; V8: 0 m; V9: 0; Verze programu: 2.2; Označení: I.D101; Plugin_Bezeichnung: MainObject; Plugin_Objektname: SmartPartCompressed; Uvažované procento prosklení: 100; Verze: 4.0; Podlaží: 1.NP; šířka: 800; výška: 2100; Funkce (venkovní): Ne; Připojení EZS: Ne; Připojení NN: Ne; Připojení EPS: Ne; Připojení MaR: Ne; Připojení ACS: Ne; Typ dveřní zarážky: Bez; Typ samozavírače: Hřebenový s kluznou lištou; Vzduchová neprůzvučnost: 0; Dveře_Světlá-šířka: 0 m; Dveře_Světlá-výška: 0 m; Zárubeň/Rám_Typ: dvoudílná; Zárubeň/Rám_Materiál: Ocelová; Zárubeň/Rám_Povrch: komaxit; Křídlo_Materiál: Dřevěné; Křídlo_Povrch_Int.: HPL laminát; Křídlo_Povrch_Ext.: HPL laminát; Kování_Klika_Int.: klika; Kování_Klika_Ext.: koule; Kování_Zámek: mechanický vložkový; Specifikace: Interiérové dveře jednokřídlé plné; Allright_Stavebni_dil_ID: 1464Obj1096312996; Jednotka: Kus; Název_objektu: Dveře - objekt+SmartPart; GlassSurface: 0; HeightWindowSillOutside: 0; HeightWindowSillInside: 0; OffsetOpeningBottom: 0; OffsetOpeningTop: 0; OffsetOpeningLeft: 0; OffsetOpeningRight: 0; DeductionOpeningBottom: 300; DeductionOpeningLeft: 50; DeductionOpeningRight: 50; DeductionOpeningTop: 50
Pset_DoorCommon - Status: NEW; IsExternal: no; ThermalTransmittance: 0 W/K/m2; HandicapAccessible: no; SmokeStop: no; SelfClosing: no; FireExit: no; SecurityRating: bez
Qto_DoorBaseQuantities - Height: 2.45 m; Width: 0.9 m; Area: 2.205 m2; Perimeter: 0 m

# IfcDoor: I.D102
In: Půdorys 1.NP
Type - PredefinedType: DOOR; ParameterTakesPrecedence: no
OverallHeight: 2.12 m; OverallWidth: 1 m
NEMSOK - Kód prvku: DD01.03.0102; Jednotková_cena: 0; V6: 0 m; V7: 0 m; V8: 0 m; V9: 0; Verze programu: 2.2; Označení: I.D102; Plugin_Bezeichnung: MainObject; Plugin_Objektname: SmartPartCompressed; Uvažované procento prosklení: 100; Verze: 4.0; Podlaží: 1.NP; šířka: 900; výška: 1970; Funkce (venkovní): Ne; Připojení EZS: Ne; Připojení NN: Ne; Připojení EPS: Ne; Připojení MaR: Ne; Připojení ACS: Ne; Typ dveřní zarážky: Bez; Typ samozavírače: Hřebenový s kluznou lištou; Vzduchová neprůzvučnost: 0; Dveře_Světlá-šířka: 0 m; Dveře_Světlá-výška: 0 m; Zárubeň/Rám_Typ: dvoudílná; Zárubeň/Rám_Materiál: Ocelová; Zárubeň/Rám_Povrch: komaxit; Křídlo_Materiál: Dřevěné; Křídlo_Povrch_Int.: HPL laminát; Křídlo_Povrch_Ext.: HPL laminát; Kování_Klika_Int.: klika; Kování_Klika_Ext.: koule; Kování_Zámek: mechanický vložkový; Specifikace: Interiérové dveře jednokřídlé plné; Allright_Stavebni_dil_ID: 1464Obj1096216571; Jednotka: Kus; Název_objektu: Dveře - objekt+SmartPart; GlassSurface: 0.1; HeightWindowSillOutside: 0; HeightWindowSillInside: 0; OffsetOpeningBottom: 0; OffsetOpeningTop: 0; OffsetOpeningLeft: 0; OffsetOpeningRight: 0; DeductionOpeningBottom: 100; DeductionOpeningLeft: 50; DeductionOpeningRight: 50; DeductionOpeningTop: 50
Pset_DoorCommon - Status: NEW; IsExternal: no; FireRating: EW 30DP3-C; ThermalTransmittance: 0 W/K/m2; HandicapAccessible: no; SmokeStop: no; SelfClosing: no; FireExit: no; SecurityRating: bez
Qto_DoorBaseQuantities - Height: 2.12 m; Width: 1 m; Area: 2.12 m2; Perimeter: 0 m

# IfcDoor: I.D103
In: Půdorys 1.NP
Type - PredefinedType: DOOR; ParameterTakesPrecedence: no
OverallHeight: 2.12 m; OverallWidth: 1 m
NEMSOK - Kód prvku: DD01.03.0103; Jednotková_cena: 0; V6: 0 m; V7: 0 m; V8: 0 m; V9: 0; Verze programu: 2.2; Označení: I.D103; Plugin_Bezeichnung: MainObject; Plugin_Objektname: SmartPartCompressed; Uvažované procento prosklení: 100; Verze: 4.0; Podlaží: 1.NP; šířka: 900; výška: 1970; Funkce (venkovní): Ne; Připojení EZS: Ne; Připojení NN: Ne; Připojení EPS: Ne; Připojení MaR: Ne; Připojení ACS: Ne; Typ dveřní zarážky: Bez; Typ samozavírače: Hřebenový s kluznou lištou; Vzduchová neprůzvučnost: 0; Dveře_Světlá-šířka: 0 m; Dveře_Světlá-výška: 0 m; Zárubeň/Rám_Typ: dvoudílná; Zárubeň/Rám_Materiál: Ocelová; Zárubeň/Rám_Povrch: komaxit; Křídlo_Materiál: Dřevěné; Křídlo_Povrch_Int.: HPL laminát; Křídlo_Povrch_Ext.: HPL laminát; Kování_Klika_Int.: klika; Kování_Klika_Ext.: koule; Kování_Zámek: mechanický vložkový; Specifikace: Interiérové dveře jednokřídlé plné; Allright_Stavebni_dil_ID: 1464Obj1096288787; Jednotka: Kus; Název_objektu: Dveře - objekt+SmartPart; GlassSurface: 0.1; HeightWindowSillOutside: 0; HeightWindowSillInside: 0; OffsetOpeningBottom: 0; OffsetOpeningTop: 0; OffsetOpeningLeft: 0; OffsetOpeningRight: 0; DeductionOpeningBottom: 100; DeductionOpeningLeft: 50; DeductionOpeningRight: 50; DeductionOpeningTop: 50
Pset_DoorCommon - Status: NEW; IsExternal: no; FireRating: EW 30DP3-C; ThermalTransmittance: 0 W/K/m2; HandicapAccessible: no; SmokeStop: no; SelfClosing: no; FireExit: no; SecurityRating: bez
Qto_DoorBaseQuantities - Height: 2.12 m; Width: 1 m; Area: 2.12 m2; Perimeter: 0 m

# IfcDoor: I.D104
In: Půdorys 1.NP
Type - PredefinedType: DOOR; ParameterTakesPrecedence: no
OverallHeight: 2.12 m; OverallWidth: 1 m
NEMSOK - Kód prvku: DD01.03.0104; Jednotková_cena: 0; V6: 0 m; V7: 0 m; V8: 0 m; V9: 0; Verze programu: 2.2; Označení: I.D104; Plugin_Bezeichnung: MainObject; Plugin_Objektname: SmartPartCompressed; Uvažované procento prosklení: 100; Verze: 4.0; Podlaží: 1.NP; šířka: 900; výška: 1970; Funkce (venkovní): Ne; Připojení EZS: Ne; Připojení NN: Ne; Připojení EPS: Ne; Připojení MaR: Ne; Připojení ACS: Ne; Typ dveřní zarážky: Bez; Typ samozavírače: bez; Vzduchová neprůzvučnost: 0; Dveře_Světlá-šířka: 0 m; Dveře_Světlá-výška: 0 m; Zárubeň/Rám_Typ: dvoudílná; Zárubeň/Rám_Materiál: Ocelová; Zárubeň/Rám_Povrch: komaxit; Křídlo_Materiál: Dřevěné; Křídlo_Povrch_Int.: HPL laminát; Křídlo_Povrch_Ext.: HPL laminát; Kování_Klika_Int.: klika; Kování_Klika_Ext.: klika; Kování_Zámek: mechanický vložkový; Specifikace: Interiérové dveře jednokřídlé plné; Allright_Stavebni_dil_ID: 1464Obj1096313478; Jednotka: Kus; Název_objektu: Dveře - objekt+SmartPart; GlassSurface: 0.1; HeightWindowSillOutside: 0; HeightWindowSillInside: 0; OffsetOpeningBottom: 0; OffsetOpeningTop: 0; OffsetOpeningLeft: 0; OffsetOpeningRight: 0; DeductionOpeningBottom: 100; DeductionOpeningLeft: 50; DeductionOpeningRight: 50; DeductionOpeningTop: 50
Pset_DoorCommon - Status: NEW; IsExternal: no; ThermalTransmittance: 0 W/K/m2; HandicapAccessible: no; SmokeStop: no; SelfClosing: no; FireExit: no; SecurityRating: bez
Qto_DoorBaseQuantities - Height: 2.12 m; Width: 1 m; Area: 2.12 m2; Perimeter: 0 m

# IfcDoor: I.D105
In: Půdorys 1.NP
Type - PredefinedType: DOOR; ParameterTakesPrecedence: no
OverallHeight: 2.12 m; OverallWidth: 0.9 m
NEMSOK - Kód prvku: DD01.03.0105; Jednotková_cena: 0; V6: 0 m; V7: 0 m; V8: 0 m; V9: 0; Verze programu: 2.2; Označení: I.D105; Plugin_Bezeichnung: MainObject; Plugin_Objektname: SmartPartCompressed; Uvažované procento prosklení: 100; Verze: 4.0; Podlaží: 1.NP; šířka: 800; výška: 1970; Funkce (venkovní): Ne; Připojení EZS: Ne; Připojení NN: Ne; Připojení EPS: Ne; Připojení MaR: Ne; Připojení ACS: Ne; Typ dveřní zarážky: Plastová nástěnná; Typ samozavírače: Hřebenový s kluznou lištou; Vzduchová neprůzvučnost: 0; Dveře_Světlá-šířka: 0 m; Dveře_Světlá-výška: 0 m; Zárubeň/Rám_Typ: dvoudílná; Zárubeň/Rám_Materiál: Ocelová; Zárubeň/Rám_Povrch: komaxit; Křídlo_Materiál: Dřevěné; Křídlo_Povrch_Int.: HPL laminát; Křídlo_Povrch_Ext.: HPL laminát; Kování_Klika_Int.: klika; Kování_Klika_Ext.: klika; Kování_Zámek: mechanický vložkový; Specifikace: Interiérové dveře jednokřídlé plné; Allright_Stavebni_dil_ID: 1464Obj1096313848; Jednotka: Kus; Název_objektu: Dveře - objekt+SmartPart; GlassSurface: 0.09; HeightWindowSillOutside: 0; HeightWindowSillInside: 0; OffsetOpeningBottom: 0; OffsetOpeningTop: 0; OffsetOpeningLeft: 0; OffsetOpeningRight: 0; DeductionOpeningBottom: 100; DeductionOpeningLeft: 50; DeductionOpeningRight: 50; DeductionOpeningTop: 50
Pset_DoorCommon - Status: NEW; IsExternal: no; ThermalTransmittance: 0 W/K/m2; HandicapAccessible: no; SmokeStop: no; SelfClosing: no; FireExit: no; SecurityRating: bez
Qto_DoorBaseQuantities - Height: 2.12 m; Width: 0.9 m; Area: 1.908 m2; Perimeter: 0 m

# IfcDoor: I.D106
In: Půdorys 1.NP
Type - PredefinedType: DOOR; ParameterTakesPrecedence: no
OverallHeight: 2.12 m; OverallWidth: 0.9 m
NEMSOK - Kód prvku: DD01.03.0106; Jednotková_cena: 0; V6: 0 m; V7: 0 m; V8: 0 m; V9: 0; Verze programu: 2.2; Označení: I.D106; Plugin_Bezeichnung: MainObject; Plugin_Objektname: SmartPartCompressed; Uvažované procento prosklení: 100; Verze: 4.0; Podlaží: 1.NP; šířka: 800; výška: 1970; Funkce (venkovní): Ne; Připojení EZS: Ne; Připojení NN: Ne; Připojení EPS: Ne; Připojení MaR: Ne; Připojení ACS: Ne; Typ dveřní zarážky: Bez; Typ samozavírače: Hřebenový s kluznou lištou; Vzduchová neprůzvučnost: 0; Dveře_Světlá-šířka: 0 m; Dveře_Světlá-výška: 0 m; Zárubeň/Rám_Typ: dvoudílná; Zárubeň/Rám_Materiál: Ocelová; Zárubeň/Rám_Povrch: komaxit; Křídlo_Materiál: Dřevěné; Křídlo_Povrch_Int.: HPL laminát; Křídlo_Povrch_Ext.: HPL laminát; Kování_Klika_Int.: klika; Kování_Klika_Ext.: klika; Kování_Zámek: mechanický vložkový; Specifikace: Interiérové dveře jednokřídlé plné; Allright_Stavebni_dil_ID: 1464Obj1096313990; Jednotka: Kus; Název_objektu: Dveře - objekt+SmartPart; GlassSurface: 0.09; HeightWindowSillOutside: 0; HeightWindowSillInside: 0; OffsetOpeningBottom: 0; OffsetOpeningTop: 0; OffsetOpeningLeft: 0; OffsetOpeningRight: 0; DeductionOpeningBottom: 100; DeductionOpeningLeft: 50; DeductionOpeningRight: 50; DeductionOpeningTop: 50
Pset_DoorCommon - Status: NEW; IsExternal: no; ThermalTransmittance: 0 W/K/m2; HandicapAccessible: no; SmokeStop: no; SelfClosing: no; FireExit: no; SecurityRating: bez
Qto_DoorBaseQuantities - Height: 2.12 m; Width: 0.9 m; Area: 1.908 m2; Perimeter: 0 m

# IfcDoor: I.D107
In: Půdorys 1.NP
Type - PredefinedType: DOOR; ParameterTakesPrecedence: no
OverallHeight: 2.12 m; OverallWidth: 0.8 m
NEMSOK - Kód prvku: DD01.03.0107; Jednotková_cena: 0; V6: 0 m; V7: 0 m; V8: 0 m; V9: 0; Verze programu: 2.2; Označení: I.D107; Plugin_Bezeichnung: MainObject; Plugin_Objektname: SmartPartCompressed; Uvažované procento prosklení: 100; Verze: 4.0; Podlaží: 1.NP; šířka: 700; výška: 1970; Funkce (venkovní): Ne; Připojení EZS: Ne; Připojení NN: Ne; Připojení EPS: Ne; Připojení MaR: Ne; Připojení ACS: Ne; Typ dveřní zarážky: Plastová nástěnná; Typ samozavírače: Hřebenový s kluznou lištou; Vzduchová neprůzvučnost: 0; Dveře_Světlá-šířka: 0 m; Dveře_Světlá-výška: 0 m; Zárubeň/Rám_Typ: pro zazdění; Zárubeň/Rám_Materiál: Ocelová; Zárubeň/Rám_Povrch: komaxit; Křídlo_Materiál: Dřevěné; Křídlo_Povrch_Int.: HPL laminát; Křídlo_Povrch_Ext.: HPL laminát; Kování_Klika_Int.: klika; Kování_Klika_Ext.: klika; Kování_Zámek: WC zámek; Specifikace: Interiérové dveře jednokřídlé plné; Allright_Stavebni_dil_ID: 1464Obj1096161102; Jednotka: Kus; Název_objektu: Dveře - objekt+SmartPart; GlassSurface: 0.08; HeightWindowSillOutside: 0; HeightWindowSillInside: 0; OffsetOpeningBottom: 0; OffsetOpeningTop: 0; OffsetOpeningLeft: 0; OffsetOpeningRight: 0; DeductionOpeningBottom: 100; DeductionOpeningLeft: 50; DeductionOpeningRight: 50; DeductionOpeningTop: 50
Pset_DoorCommon - Status: NEW; IsExternal: no; ThermalTransmittance: 0 W/K/m2; HandicapAccessible: no; SmokeStop: no; SelfClosing: no; FireExit: no; SecurityRating: bez
Qto_DoorBaseQuantities - Height: 2.12 m; Width: 0.8 m; Area: 1.696 m2; Perimeter: 0 m

# IfcDoor: I.D108
In: Půdorys 1.NP
Type - PredefinedType: DOOR; ParameterTakesPrecedence: no
OverallHeight: 2.12 m; OverallWidth: 0.9 m
NEMSOK - Kód prvku: DD01.03.0108; Jednotková_cena: 0; V6: 0 m; V7: 0 m; V8: 0 m; V9: 0; Verze programu: 2.2; Označení: I.D108; Plugin_Bezeichnung: MainObject; Plugin_Objektname: SmartPartCompressed; Uvažované procento prosklení: 100; Verze: 4.0; Podlaží: 1.NP; šířka: 800; výška: 1970; Funkce (venkovní): Ne; Připojení EZS: Ne; Připojení NN: Ne; Připojení EPS: Ne; Připojení MaR: Ne; Připojení ACS: Ne; Typ dveřní zarážky: Bez; Typ samozavírače: Hřebenový s kluznou lištou; Vzduchová neprůzvučnost: 0; Dveře_Světlá-šířka: 0 m; Dveře_Světlá-výška: 0 m; Zárubeň/Rám_Typ: dvoudílná; Zárubeň/Rám_Materiál: Ocelová; Zárubeň/Rám_Povrch: komaxit; Křídlo_Materiál: Dřevěné; Křídlo_Povrch_Int.: HPL laminát; Křídlo_Povrch_Ext.: HPL laminát; Kování_Klika_Int.: klika; Kování_Klika_Ext.: koule; Kování_Zámek: mechanický vložkový; Specifikace: Interiérové dveře jednokřídlé plné; Allright_Stavebni_dil_ID: 1464Obj1096163807; Jednotka: Kus; Název_objektu: Dveře - objekt+SmartPart; GlassSurface: 0.09; HeightWindowSillOutside: 0; HeightWindowSillInside: 0; OffsetOpeningBottom: 0; OffsetOpeningTop: 0; OffsetOpeningLeft: 0; OffsetOpeningRight: 0; DeductionOpeningBottom: 100; DeductionOpeningLeft: 50; DeductionOpeningRight: 50; DeductionOpeningTop: 50
Pset_DoorCommon - Status: NEW; IsExternal: no; ThermalTransmittance: 0 W/K/m2; HandicapAccessible: no; SmokeStop: no; SelfClosing: no; FireExit: no; SecurityRating: bez
Qto_DoorBaseQuantities - Height: 2.12 m; Width: 0.9 m; Area: 1.908 m2; Perimeter: 0 m

# IfcDoor: I.D109
In: Půdorys 1.NP
Type - PredefinedType: DOOR; ParameterTakesPrecedence: no
OverallHeight: 2.12 m; OverallWidth: 0.9 m
NEMSOK - Kód prvku: DD01.03.0109; Jednotková_cena: 0; V6: 0 m; V7: 0 m; V8: 0 m; V9: 0; Verze programu: 2.2; Označení: I.D109; Plugin_Bezeichnung: MainObject; Plugin_Objektname: SmartPartCompressed; Uvažované procento prosklení: 100; Verze: 4.0; Podlaží: 1.NP; šířka: 800; výška: 1970; Funkce (venkovní): Ne; Připojení EZS: Ne; Připojení NN: Ne; Připojení EPS: Ne; Připojení MaR: Ne; Připojení ACS: Ne; Typ dveřní zarážky: Plastová nástěnná; Typ samozavírače: Hřebenový s kluznou lištou; Vzduchová neprůzvučnost: 0; Dveře_Světlá-šířka: 0 m; Dveře_Světlá-výška: 0 m; Zárubeň/Rám_Typ: dvoudílná; Zárubeň/Rám_Materiál: Ocelová; Zárubeň/Rám_Povrch: komaxit; Křídlo_Materiál: Dřevěné; Křídlo_Povrch_Int.: HPL laminát; Křídlo_Povrch_Ext.: HPL laminát; Kování_Klika_Int.: klika; Kování_Klika_Ext.: koule; Kování_Zámek: mechanický vložkový; Specifikace: Interiérové dveře jednokřídlé plné; Allright_Stavebni_dil_ID: 1464Obj1096313711; Jednotka: Kus; Název_objektu: Dveře - objekt+SmartPart; GlassSurface: 0.09; HeightWindowSillOutside: 0; HeightWindowSillInside: 0; OffsetOpeningBottom: 0; OffsetOpeningTop: 0; OffsetOpeningLeft: 0; OffsetOpeningRight: 0; DeductionOpeningBottom: 100; DeductionOpeningLeft: 50; DeductionOpeningRight: 50; DeductionOpeningTop: 50
Pset_DoorCommon - Status: NEW; IsExternal: no; ThermalTransmittance: 0 W/K/m2; HandicapAccessible: no; SmokeStop: no; SelfClosing: no; FireExit: no; SecurityRating: bez
Qto_DoorBaseQuantities - Height: 2.12 m; Width: 0.9 m; Area: 1.908 m2; Perimeter: 0 m

# IfcDoor: I.D110
In: Půdorys 1.NP
Type - PredefinedType: DOOR; ParameterTakesPrecedence: no
OverallHeight: 2.12 m; OverallWidth: 0.8 m
NEMSOK - Kód prvku: DD01.03.0110; Jednotková_cena: 0; V6: 0 m; V7: 0 m; V8: 0 m; V9: 0; Verze programu: 2.2; Označení: I.D110; Plugin_Bezeichnung: MainObject; Plugin_Objektname: SmartPartCompressed; Uvažované procento prosklení: 100; Verze: 4.0; Podlaží: 1.NP; šířka: 700; výška: 1970; Funkce (venkovní): Ne; Připojení EZS: Ne; Připojení NN: Ne; Připojení EPS: Ne; Připojení MaR: Ne; Připojení ACS: Ne; Typ dveřní zarážky: Plastová nástěnná; Typ samozavírače: Hřebenový s kluznou lištou; Vzduchová neprůzvučnost: 0; Dveře_Světlá-šířka: 0 m; Dveře_Světlá-výška: 0 m; Zárubeň/Rám_Typ: dvoudílná; Zárubeň/Rám_Materiál: Ocelová; Zárubeň/Rám_Povrch: komaxit; Křídlo_Materiál: Dřevěné; Křídlo_Povrch_Int.: HPL laminát; Křídlo_Povrch_Ext.: HPL laminát; Kování_Klika_Int.: klika; Kování_Klika_Ext.: klika; Kování_Zámek: WC zámek; Specifikace: Interiérové dveře jednokřídlé plné; Allright_Stavebni_dil_ID: 1464Obj1096313779; Jednotka: Kus; Název_objektu: Dveře - objekt+SmartPart; GlassSurface: 0.08; HeightWindowSillOutside: 0; HeightWindowSillInside: 0; OffsetOpeningBottom: 0; OffsetOpeningTop: 0; OffsetOpeningLeft: 0; OffsetOpeningRight: 0; DeductionOpeningBottom: 100; DeductionOpeningLeft: 50; DeductionOpeningRight: 50; DeductionOpeningTop: 50
Pset_DoorCommon - Status: NEW; IsExternal: no; ThermalTransmittance: 0 W/K/m2; HandicapAccessible: no; SmokeStop: no; SelfClosing: no; FireExit: no; SecurityRating: bez
Qto_DoorBaseQuantities - Height: 2.12 m; Width: 0.8 m; Area: 1.696 m2; Perimeter: 0 m

# IfcDoor: I.D111
In: Půdorys 1.NP
Type - PredefinedType: DOOR; ParameterTakesPrecedence: no
OverallHeight: 2.12 m; OverallWidth: 1.55 m
NEMSOK - Kód prvku: DD01.03.0111; Jednotková_cena: 0; V6: 0 m; V7: 0 m; V8: 0 m; V9: 0; Verze programu: 2.2; Označení: I.D111; Plugin_Bezeichnung: MainObject; Plugin_Objektname: SmartPartCompressed; Uvažované procento prosklení: 100; Verze: 4.0; Podlaží: 1.NP; šířka: 1450; výška: 1970; Funkce (venkovní): Ne; Připojení EZS: Ne; Připojení NN: Ne; Připojení EPS: Ne; Připojení MaR: Ne; Připojení ACS: Ano; Typ dveřní zarážky: Bez; Typ samozavírače: Hřebenový s kluznou lištou + požární konzole; Vzduchová neprůzvučnost: 0; Dveře_Světlá-šířka: 0.9 m; Dveře_Světlá-výška: 0 m; Zárubeň/Rám_Typ: dvoudílná; Zárubeň/Rám_Materiál: Ocelová; Zárubeň/Rám_Povrch: komaxit; Křídlo_Materiál: Dřevěné; Křídlo_Povrch_Int.: HPL laminát; Křídlo_Povrch_Ext.: HPL laminát; Kování_Klika_Int.: klika; Kování_Klika_Ext.: paniková klika; Kování_Zámek: mechanický vložkový; Specifikace: Interiérové dveře dvoukřídlé plné; Allright_Stavebni_dil_ID: 1464Obj1096157586; Jednotka: Kus; Název_objektu: Dveře - objekt+SmartPart; GlassSurface: 0.15345; HeightWindowSillOutside: 0; HeightWindowSillInside: 0; OffsetOpeningBottom: 0; OffsetOpeningTop: 0; OffsetOpeningLeft: 0; OffsetOpeningRight: 0; DeductionOpeningBottom: 100; DeductionOpeningLeft: 50; DeductionOpeningRight: 50; DeductionOpeningTop: 50
Pset_DoorCommon - Status: NEW; IsExternal: no; FireRating: EI 30DP3-Sm-C; ThermalTransmittance: 0 W/K/m2; HandicapAccessible: no; SmokeStop: no; SelfClosing: no; FireExit: no; SecurityRating: bez
Qto_DoorBaseQuantities - Height: 2.12 m; Width: 1.55 m; Area: 3.286 m2; Perimeter: 0 m

# IfcDoor: I.D112
In: Půdorys 1.NP
Type - PredefinedType: DOOR; ParameterTakesPrecedence: no
OverallHeight: 2.45 m; OverallWidth: 1 m
NEMSOK - Kód prvku: DD01.03.0112; Jednotková_cena: 0; V6: 0 m; V7: 0 m; V8: 0 m; V9: 0; Verze programu: 2.2; Označení: I.D112; Plugin_Bezeichnung: MainObject; Plugin_Objektname: SmartPartCompressed; Uvažované procento prosklení: 100; Verze: 4.0; Podlaží: 1.NP; šířka: 900; výška: 2100; Funkce (venkovní): Ne; Připojení EZS: Ne; Připojení NN: Ne; Připojení EPS: Ne; Připojení MaR: Ne; Připojení ACS: Ne; Typ dveřní zarážky: Plastová nástěnná; Typ samozavírače: bez; Vzduchová neprůzvučnost: 32; Dveře_Světlá-šířka: 0 m; Dveře_Světlá-výška: 0 m; Zárubeň/Rám_Typ: dvoudílná; Zárubeň/Rám_Materiál: Ocelová; Zárubeň/Rám_Povrch: komaxit; Křídlo_Materiál: Dřevěné; Křídlo_Povrch_Int.: HPL laminát; Křídlo_Povrch_Ext.: HPL laminát; Kování_Klika_Int.: klika; Kování_Klika_Ext.: klika; Kování_Zámek: mechanický vložkový; Specifikace: Interiérové dveře jednokřídlé plné; Allright_Stavebni_dil_ID: 1464Obj1096159635; Jednotka: Kus; Název_objektu: Dveře - objekt+SmartPart; GlassSurface: 0; HeightWindowSillOutside: 0; HeightWindowSillInside: 0; OffsetOpeningBottom: 0; OffsetOpeningTop: 0; OffsetOpeningLeft: 0; OffsetOpeningRight: 0; DeductionOpeningBottom: 300; DeductionOpeningLeft: 50; DeductionOpeningRight: 50; DeductionOpeningTop: 50
Pset_DoorCommon - Status: NEW; IsExternal: no; ThermalTransmittance: 0 W/K/m2; AcousticRating: 32 dB; HandicapAccessible: no; SmokeStop: no; SelfClosing: no; FireExit: no; SecurityRating: bez
Qto_DoorBaseQuantities - Height: 2.45 m; Width: 1 m; Area: 2.45 m2; Perimeter: 0 m

# IfcDoor: I.D113
In: Půdorys 1.NP
Type - PredefinedType: DOOR; ParameterTakesPrecedence: no
OverallHeight: 2.45 m; OverallWidth: 1 m
NEMSOK - Kód prvku: DD01.03.0113; Jednotková_cena: 0; V6: 0 m; V7: 0 m; V8: 0 m; V9: 0; Verze programu: 2.2; Označení: I.D113; Plugin_Bezeichnung: MainObject; Plugin_Objektname: SmartPartCompressed; Uvažované procento prosklení: 100; Verze: 4.0; Podlaží: 1.NP; šířka: 900; výška: 2100; Funkce (venkovní): Ne; Připojení EZS: Ne; Připojení NN: Ne; Připojení EPS: Ne; Připojení MaR: Ne; Připojení ACS: Ne; Typ dveřní zarážky: Bez; Typ samozavírače: bez; Vzduchová neprůzvučnost: 0; Dveře_Světlá-šířka: 0 m; Dveře_Světlá-výška: 0 m; Zárubeň/Rám_Typ: dvoudílná; Zárubeň/Rám_Materiál: Ocelová; Zárubeň/Rám_Povrch: komaxit; Křídlo_Materiál: Dřevěné; Křídlo_Povrch_Int.: HPL laminát; Křídlo_Povrch_Ext.: HPL laminát; Kování_Klika_Int.: klika; Kování_Klika_Ext.: klika; Kování_Zámek: mechanický vložkový; Specifikace: Interiérové dveře jednokřídlé plné; Allright_Stavebni_dil_ID: 1464Obj1096159630; Jednotka: Kus; Název_objektu: Dveře - objekt+SmartPart; GlassSurface: 0; HeightWindowSillOutside: 0; HeightWindowSillInside: 0; OffsetOpeningBottom: 0; OffsetOpeningTop: 0; OffsetOpeningLeft: 0; OffsetOpeningRight: 0; DeductionOpeningBottom: 300; DeductionOpeningLeft: 50; DeductionOpeningRight: 50; DeductionOpeningTop: 50
Pset_DoorCommon - Status: NEW; IsExternal: no; ThermalTransmittance: 0 W/K/m2; HandicapAccessible: no; SmokeStop: no; SelfClosing: no; FireExit: no; SecurityRating: bez
Qto_DoorBaseQuantities - Height: 2.45 m; Width: 1 m; Area: 2.45 m2; Perimeter: 0 m

# IfcDoor: I.D114
In: Půdorys 1.NP
Type - PredefinedType: DOOR; ParameterTakesPrecedence: no
OverallHeight: 2.45 m; OverallWidth: 1 m
NEMSOK - Kód prvku: DD01.03.0114; Jednotková_cena: 0; V6: 0 m; V7: 0 m; V8: 0 m; V9: 0; Verze programu: 2.2; Označení: I.D114; Plugin_Bezeichnung: MainObject; Plugin_Objektname: SmartPartCompressed; Uvažované procento prosklení: 100; Verze: 4.0; Podlaží: 1.NP; šířka: 900; výška: 2100; Funkce (venkovní): Ne; Připojení EZS: Ne; Připojení NN: Ne; Připojení EPS: Ne; Připojení MaR: Ne; Připojení ACS: Ne; Typ dveřní zarážky: Plastová nástěnná; Typ samozavírače: bez; Vzduchová neprůzvučnost: 0; Dveře_Světlá-šířka: 0 m; Dveře_Světlá-výška: 0 m; Zárubeň/Rám_Typ: dvoudílná; Zárubeň/Rám_Materiál: Ocelová; Zárubeň/Rám_Povrch: komaxit; Křídlo_Materiál: Dřevěné; Křídlo_Povrch_Int.: HPL laminát; Křídlo_Povrch_Ext.: HPL laminát; Kování_Klika_Int.: klika; Kování_Klika_Ext.: klika; Kování_Zámek: mechanický vložkový; Specifikace: Interiérové dveře jednokřídlé plné; Allright_Stavebni_dil_ID: 1464Obj1096159626; Jednotka: Kus; Název_objektu: Dveře - objekt+SmartPart; GlassSurface: 0; HeightWindowSillOutside: 0; HeightWindowSillInside: 0; OffsetOpeningBottom: 0; OffsetOpeningTop: 0; OffsetOpeningLeft: 0; OffsetOpeningRight: 0; DeductionOpeningBottom: 300; DeductionOpeningLeft: 50; DeductionOpeningRight: 50; DeductionOpeningTop: 50
Pset_DoorCommon - Status: NEW; IsExternal: no; ThermalTransmittance: 0 W/K/m2; HandicapAccessible: no; SmokeStop: no; SelfClosing: no; FireExit: no; SecurityRating: bez
Qto_DoorBaseQuantities - Height: 2.45 m; Width: 1 m; Area: 2.45 m2; Perimeter: 0 m

# IfcDoor: I.DF01
In: Půdorys 1.NP
Type - PredefinedType: DOOR; ParameterTakesPrecedence: no
OverallHeight: 2.44 m; OverallWidth: 1.88 m
NEMSOK - Kód prvku: DD03.03.1101; Jednotková_cena: 0; V6: 0 m; V7: 0 m; V8: 0 m; V9: 0; Verze programu: 2.2; Označení: I.DF01; Plugin_Bezeichnung: MainObject; Plugin_Objektname: SmartPartCompressed; Uvažované procento prosklení: 100; Verze: 4.0; Podlaží: 1.NP; šířka: 1800; výška: 2100; Funkce (venkovní): Ano; Připojení EZS: Ne; Připojení NN: Ano; Připojení EPS: Ano; Připojení MaR: Ne; Připojení ACS: Ne; Typ dveřní zarážky: Bez; Typ samozavírače: bez; Vzduchová neprůzvučnost: 0; Dveře_Světlá-šířka: 0 m; Dveře_Světlá-výška: 0 m; Zárubeň/Rám_Typ: rámová; Zárubeň/Rám_Materiál: Hliníková; Zárubeň/Rám_Povrch: elox; Křídlo_Materiál: Hliníkové; Kování_Klika_Int.: radar; Kování_Klika_Ext.: radar; Kování_Zámek: bez; Specifikace: Vchodové dveře dvoupanelové prosklené v prosklené fasádě; Allright_Stavebni_dil_ID: 1464Obj1096159307; Jednotka: Kus; Název_objektu: Dveře - objekt+SmartPart; GlassSurface: 2.92155; HeightWindowSillOutside: 0; HeightWindowSillInside: 0; OffsetOpeningBottom: 0; OffsetOpeningTop: 0; OffsetOpeningLeft: 0; OffsetOpeningRight: 0; DeductionOpeningBottom: 300; DeductionOpeningLeft: 20; DeductionOpeningRight: 20; DeductionOpeningTop: 20
Pset_DoorCommon - Status: NEW; IsExternal: yes; ThermalTransmittance: 0.9 W/K/m2; HandicapAccessible: no; SmokeStop: no; SelfClosing: no; FireExit: no; SecurityRating: bez
Qto_DoorBaseQuantities - Height: 2.42 m; Width: 1.84 m; Area: 4.453 m2; Perimeter: 0 m

# IfcDoor: I.DF02
In: Půdorys 1.NP
Type - PredefinedType: DOOR; ParameterTakesPrecedence: no
OverallHeight: 3.05 m; OverallWidth: 3.8 m
NEMSOK - Kód prvku: DD03.03.1102; Jednotková_cena: 0; V6: 0 m; V7: 0 m; V8: 0 m; V9: 0; Verze programu: 2.2; Označení: I.DF02; Plugin_Bezeichnung: MainObject; Plugin_Objektname: SmartPartCompressed; Uvažované procento prosklení: 100; Verze: 4.0; Podlaží: 1.NP; šířka: 1800; výška: 2100; Funkce (venkovní): Ano; Připojení EZS: Ne; Připojení NN: Ano; Připojení EPS: Ano; Připojení MaR: Ne; Připojení ACS: Ano; Typ dveřní zarážky: Bez; Typ samozavírače: bez; Vzduchová neprůzvučnost: 0; Dveře_Světlá-šířka: 0 m; Dveře_Světlá-výška: 0 m; Zárubeň/Rám_Typ: rámová; Zárubeň/Rám_Materiál: Hliníková; Zárubeň/Rám_Povrch: elox; Křídlo_Materiál: Hliníkové; Kování_Klika_Int.: loketní spínač; Kování_Klika_Ext.: čtečka karet; Kování_Zámek: bez; Specifikace: Vchodové dveře dvoupanelové prosklené s proskleným nasvětlíkem; Allright_Stavebni_dil_ID: 1464Obj1096159340; Jednotka: Kus; Název_objektu: Dveře - objekt+SmartPart; GlassSurface: 7.66625; HeightWindowSillOutside: 0; HeightWindowSillInside: 0; OffsetOpeningBottom: 0; OffsetOpeningTop: 0; OffsetOpeningLeft: 0; OffsetOpeningRight: 0; DeductionOpeningBottom: 300; DeductionOpeningLeft: 1000; DeductionOpeningRight: 1000; DeductionOpeningTop: 650
Pset_DoorCommon - Status: NEW; IsExternal: yes; ThermalTransmittance: 0.9 W/K/m2; HandicapAccessible: no; SmokeStop: no; SelfClosing: no; FireExit: no; SecurityRating: bez
Qto_DoorBaseQuantities - Height: 3.05 m; Width: 3.8 m; Area: 11.59 m2; Perimeter: 0 m

# IfcDoor: I.DH01
In: Půdorys 1.NP
Type - PredefinedType: DOOR; ParameterTakesPrecedence: no
OverallHeight: 2.14 m; OverallWidth: 1.88 m
NEMSOK - Kód prvku: DD03.03.1201; Jednotková_cena: 0; V6: 0 m; V7: 0 m; V8: 0 m; V9: 0; Verze programu: 2.2; Označení: I.DH01; Plugin_Bezeichnung: MainObject; Plugin_Objektname: SmartPartCompressed; Uvažované procento prosklení: 100; Verze: 4.0; Podlaží: 1.NP; šířka: 1800; výška: 2100; Funkce (venkovní): Ne; Připojení EZS: Ne; Připojení NN: Ano; Připojení EPS: Ano; Připojení MaR: Ne; Připojení ACS: Ne; Typ dveřní zarážky: Bez; Typ samozavírače: bez; Vzduchová neprůzvučnost: 0; Dveře_Světlá-šířka: 0 m; Dveře_Světlá-výška: 0 m; Zárubeň/Rám_Typ: rámová; Zárubeň/Rám_Materiál: Hliníková; Zárubeň/Rám_Povrch: elox; Křídlo_Materiál: Hliníkové; Kování_Klika_Int.: radar; Kování_Klika_Ext.: radar; Kování_Zámek: bez; Specifikace: Interiérové dveře automatické posuvné dvoupanelové prosklené; Allright_Stavebni_dil_ID: 1464Obj1096159794; Jednotka: Kus; Název_objektu: Dveře - objekt+SmartPart; GlassSurface: 2.92305; HeightWindowSillOutside: 0; HeightWindowSillInside: 0; OffsetOpeningBottom: 0; OffsetOpeningTop: 0; OffsetOpeningLeft: 0; OffsetOpeningRight: 0; DeductionOpeningBottom: 0; DeductionOpeningLeft: 20; DeductionOpeningRight: 20; DeductionOpeningTop: 20
Pset_DoorCommon - Status: NEW; IsExternal: no; ThermalTransmittance: 0 W/K/m2; HandicapAccessible: no; SmokeStop: no; SelfClosing: no; FireExit: no; SecurityRating: bez
Qto_DoorBaseQuantities - Height: 2.12 m; Width: 1.84 m; Area: 3.901 m2; Perimeter: 0 m

# IfcDoor: I.DH02
In: Půdorys 1.NP
Type - PredefinedType: DOOR; ParameterTakesPrecedence: no
OverallHeight: 2.44 m; OverallWidth: 1.58 m
NEMSOK - Kód prvku: DD03.03.1202; Jednotková_cena: 0; V6: 0 m; V7: 0 m; V8: 0 m; V9: 0; Verze programu: 2.2; Označení: I.DH02; Plugin_Bezeichnung: MainObject; Plugin_Objektname: SmartPartCompressed; Uvažované procento prosklení: 100; Verze: 4.0; Podlaží: 1.NP; šířka: 1500; výška: 2100; Funkce (venkovní): Ne; Připojení EZS: Ne; Připojení NN: Ano; Připojení EPS: Ne; Připojení MaR: Ne; Připojení ACS: Ano; Typ dveřní zarážky: Bez; Typ samozavírače: bez; Vzduchová neprůzvučnost: 0; Dveře_Světlá-šířka: 0 m; Dveře_Světlá-výška: 0 m; Zárubeň/Rám_Typ: rámová; Zárubeň/Rám_Materiál: Hliníková; Zárubeň/Rám_Povrch: elox; Křídlo_Materiál: Hliníkové; Kování_Klika_Int.: čtečka karet; Kování_Klika_Ext.: loketní spínač; Kování_Zámek: bez; Specifikace: Interiérové dveře automatické posuvné dvoupanelové teleskopické plné; Allright_Stavebni_dil_ID: 1464Obj1096213442; Jednotka: Kus; Název_objektu: Dveře - objekt+SmartPart; GlassSurface: 2.5967; HeightWindowSillOutside: 0; HeightWindowSillInside: 0; OffsetOpeningBottom: 0; OffsetOpeningTop: 0; OffsetOpeningLeft: 0; OffsetOpeningRight: 0; DeductionOpeningBottom: 300; DeductionOpeningLeft: 20; DeductionOpeningRight: 20; DeductionOpeningTop: 20
Pset_DoorCommon - Status: NEW; IsExternal: no; ThermalTransmittance: 0 W/K/m2; HandicapAccessible: no; SmokeStop: no; SelfClosing: no; FireExit: no; SecurityRating: bez
Qto_DoorBaseQuantities - Height: 2.42 m; Width: 1.54 m; Area: 3.727 m2; Perimeter: 0 m

# IfcDoor: I.DH03
In: Půdorys 1.NP
Type - PredefinedType: DOOR; ParameterTakesPrecedence: no
OverallHeight: 2.44 m; OverallWidth: 1.58 m
NEMSOK - Kód prvku: DD03.03.1203; Jednotková_cena: 0; V6: 0 m; V7: 0 m; V8: 0 m; V9: 0; Verze programu: 2.2; Označení: I.DH03; Plugin_Bezeichnung: MainObject; Plugin_Objektname: SmartPartCompressed; Uvažované procento prosklení: 100; Verze: 4.0; Podlaží: 1.NP; šířka: 1500; výška: 2100; Funkce (venkovní): Ne; Připojení EZS: Ne; Připojení NN: Ano; Připojení EPS: Ne; Připojení MaR: Ne; Připojení ACS: Ne; Typ dveřní zarážky: Bez; Typ samozavírače: bez; Vzduchová neprůzvučnost: 0; Dveře_Světlá-šířka: 0 m; Dveře_Světlá-výška: 0 m; Zárubeň/Rám_Typ: rámová; Zárubeň/Rám_Materiál: Hliníková; Zárubeň/Rám_Povrch: elox; Křídlo_Materiál: Hliníkové; Kování_Klika_Int.: loketní spínač; Kování_Klika_Ext.: loketní spínač; Kování_Zámek: bez; Specifikace: Interiérové dveře automatické posuvné dvoupanelové prosklené; Allright_Stavebni_dil_ID: 1464Obj1096312881; Jednotka: Kus; Název_objektu: Dveře - objekt+SmartPart; GlassSurface: 2.5967; HeightWindowSillOutside: 0; HeightWindowSillInside: 0; OffsetOpeningBottom: 0; OffsetOpeningTop: 0; OffsetOpeningLeft: 0; OffsetOpeningRight: 0; DeductionOpeningBottom: 300; DeductionOpeningLeft: 20; DeductionOpeningRight: 20; DeductionOpeningTop: 20
Pset_DoorCommon - Status: NEW; IsExternal: no; FireRating: EI 30DP1-Sm-C; ThermalTransmittance: 0 W/K/m2; HandicapAccessible: no; SmokeStop: no; SelfClosing: no; FireExit: no; SecurityRating: bez
Qto_DoorBaseQuantities - Height: 2.42 m; Width: 1.54 m; Area: 3.727 m2; Perimeter: 0 m

# IfcDoor: I.DH04
In: Půdorys 1.NP
Type - PredefinedType: DOOR; ParameterTakesPrecedence: no
OverallHeight: 2.24 m; OverallWidth: 1.58 m
NEMSOK - Kód prvku: DD03.03.1204; Jednotková_cena: 0; V6: 0 m; V7: 0 m; V8: 0 m; V9: 0; Verze programu: 2.2; Označení: I.DH04; Plugin_Bezeichnung: MainObject; Plugin_Objektname: SmartPartCompressed; Uvažované procento prosklení: 100; Verze: 4.0; Podlaží: 1.NP; šířka: 1500; výška: 2100; Funkce (venkovní): Ne; Připojení EZS: Ne; Připojení NN: Ano; Připojení EPS: Ano; Připojení MaR: Ne; Připojení ACS: Ne; Typ dveřní zarážky: Bez; Typ samozavírače: bez; Vzduchová neprůzvučnost: 0; Dveře_Světlá-šířka: 0 m; Dveře_Světlá-výška: 0 m; Zárubeň/Rám_Typ: rámová; Zárubeň/Rám_Materiál: Hliníková; Zárubeň/Rám_Povrch: elox; Křídlo_Materiál: Hliníkové; Kování_Klika_Int.: radar; Kování_Klika_Ext.: radar; Kování_Zámek: bez; Specifikace: Interiérové dveře automatické posuvné dvoupanelové teleskopické prosklené; Allright_Stavebni_dil_ID: 1464Obj1096158323; Jednotka: Kus; Název_objektu: Dveře - objekt+SmartPart; GlassSurface: 2.7507; HeightWindowSillOutside: 0; HeightWindowSillInside: 0; OffsetOpeningBottom: 0; OffsetOpeningTop: 0; OffsetOpeningLeft: 0; OffsetOpeningRight: 0; DeductionOpeningBottom: 100; DeductionOpeningLeft: 20; DeductionOpeningRight: 20; DeductionOpeningTop: 20
Pset_DoorCommon - Status: NEW; IsExternal: no; ThermalTransmittance: 0 W/K/m2; HandicapAccessible: no; SmokeStop: no; SelfClosing: no; FireExit: no; SecurityRating: bez
Qto_DoorBaseQuantities - Height: 2.22 m; Width: 1.54 m; Area: 3.419 m2; Perimeter: 0 m

# IfcDoor: I.DH05
In: Půdorys 1.NP
Type - PredefinedType: DOOR; ParameterTakesPrecedence: no
OverallHeight: 2.34 m; OverallWidth: 1.58 m
NEMSOK - Kód prvku: DD03.03.1205; Jednotková_cena: 0; V6: 0 m; V7: 0 m; V8: 0 m; V9: 0; Verze programu: 2.2; Označení: I.DH05; Plugin_Bezeichnung: MainObject; Plugin_Objektname: SmartPartCompressed; Uvažované procento prosklení: 100; Verze: 4.0; Podlaží: 1.NP; šířka: 1500; výška: 2200; Funkce (venkovní): Ne; Připojení EZS: Ne; Připojení NN: Ano; Připojení EPS: Ano; Připojení MaR: Ne; Připojení ACS: Ano; Typ dveřní zarážky: Bez; Typ samozavírače: bez; Vzduchová neprůzvučnost: 0; Dveře_Světlá-šířka: 0 m; Dveře_Světlá-výška: 0 m; Zárubeň/Rám_Typ: rámová; Zárubeň/Rám_Materiál: Hliníková; Zárubeň/Rám_Povrch: elox; Křídlo_Materiál: Hliníkové; Kování_Klika_Int.: čtečka karet; Kování_Klika_Ext.: radar; Kování_Zámek: bez; Specifikace: Interiérové dveře automatické posuvné dvoupanelové prosklené; Allright_Stavebni_dil_ID: 1464Obj1096313115; Jednotka: Kus; Název_objektu: Dveře - objekt+SmartPart; GlassSurface: 2.8806; HeightWindowSillOutside: 0; HeightWindowSillInside: 0; OffsetOpeningBottom: 0; OffsetOpeningTop: 0; OffsetOpeningLeft: 0; OffsetOpeningRight: 0; DeductionOpeningBottom: 100; DeductionOpeningLeft: 20; DeductionOpeningRight: 20; DeductionOpeningTop: 20
Pset_DoorCommon - Status: NEW; IsExternal: no; ThermalTransmittance: 0 W/K/m2; HandicapAccessible: no; SmokeStop: no; SelfClosing: no; FireExit: no; SecurityRating: bez
Qto_DoorBaseQuantities - Height: 2.32 m; Width: 1.54 m; Area: 3.573 m2; Perimeter: 0 m

# IfcDoor: I.DH06
In: Půdorys 1.NP
Type - PredefinedType: DOOR; ParameterTakesPrecedence: no
OverallHeight: 2.34 m; OverallWidth: 1.33 m
NEMSOK - Kód prvku: DD03.03.1206; Jednotková_cena: 0; V6: 0 m; V7: 0 m; V8: 0 m; V9: 0; Verze programu: 2.2; Označení: I.DH06; Plugin_Bezeichnung: MainObject; Plugin_Objektname: SmartPartCompressed; Uvažované procento prosklení: 100; Verze: 4.0; Podlaží: 1.NP; šířka: 1250; výška: 2200; Funkce (venkovní): Ne; Připojení EZS: Ne; Připojení NN: Ano; Připojení EPS: Ne; Připojení MaR: Ne; Připojení ACS: Ano; Typ dveřní zarážky: Bez; Typ samozavírače: bez; Vzduchová neprůzvučnost: 0; Dveře_Světlá-šířka: 0 m; Dveře_Světlá-výška: 0 m; Zárubeň/Rám_Typ: rámová; Zárubeň/Rám_Materiál: Hliníková; Zárubeň/Rám_Povrch: elox; Křídlo_Materiál: Hliníkové; Kování_Klika_Int.: čtečka karet; Kování_Klika_Ext.: loketní spínač; Kování_Zámek: bez; Specifikace: Interiérové dveře automatické posuvné dvoupanelové prosklené; Allright_Stavebni_dil_ID: 1464Obj1096164073; Jednotka: Kus; Název_objektu: Dveře - objekt+SmartPart; GlassSurface: 2.33085; HeightWindowSillOutside: 0; HeightWindowSillInside: 0; OffsetOpeningBottom: 0; OffsetOpeningTop: 0; OffsetOpeningLeft: 0; OffsetOpeningRight: 0; DeductionOpeningBottom: 100; DeductionOpeningLeft: 20; DeductionOpeningRight: 20; DeductionOpeningTop: 20
Pset_DoorCommon - Status: NEW; IsExternal: no; FireRating: EW 30DP1-C; ThermalTransmittance: 0 W/K/m2; HandicapAccessible: no; SmokeStop: no; SelfClosing: no; FireExit: no; SecurityRating: bez
Qto_DoorBaseQuantities - Height: 2.32 m; Width: 1.29 m; Area: 2.993 m2; Perimeter: 0 m

# IfcDoor: I.DH07
In: Půdorys 1.NP
Type - PredefinedType: DOOR; ParameterTakesPrecedence: no
OverallHeight: 2.24 m; OverallWidth: 1.33 m
NEMSOK - Kód prvku: DD03.03.1207; Jednotková_cena: 0; V6: 0 m; V7: 0 m; V8: 0 m; V9: 0; Verze programu: 2.2; Označení: I.DH07; Plugin_Bezeichnung: MainObject; Plugin_Objektname: SmartPartCompressed; Uvažované procento prosklení: 100; Verze: 4.0; Podlaží: 1.NP; šířka: 1250; výška: 2100; Funkce (venkovní): Ne; Připojení EZS: Ne; Připojení NN: Ano; Připojení EPS: Ne; Připojení MaR: Ne; Připojení ACS: Ne; Typ dveřní zarážky: Bez; Typ samozavírače: bez; Vzduchová neprůzvučnost: 0; Dveře_Světlá-šířka: 0 m; Dveře_Světlá-výška: 0 m; Zárubeň/Rám_Typ: rámová; Zárubeň/Rám_Materiál: Hliníková; Zárubeň/Rám_Povrch: elox; Křídlo_Materiál: Hliníkové; Kování_Klika_Int.: loketní spínač; Kování_Klika_Ext.: loketní spínač; Kování_Zámek: bez; Specifikace: Interiérové dveře automatické posuvné dvoupanelové prosklené; Allright_Stavebni_dil_ID: 1464Obj1096213949; Jednotka: Kus; Název_objektu: Dveře - objekt+SmartPart; GlassSurface: 2.22595; HeightWindowSillOutside: 0; HeightWindowSillInside: 0; OffsetOpeningBottom: 0; OffsetOpeningTop: 0; OffsetOpeningLeft: 0; OffsetOpeningRight: 0; DeductionOpeningBottom: 100; DeductionOpeningLeft: 20; DeductionOpeningRight: 20; DeductionOpeningTop: 20
Pset_DoorCommon - Status: NEW; IsExternal: no; FireRating: EI 30DP1-Sm-C; ThermalTransmittance: 0 W/K/m2; HandicapAccessible: no; SmokeStop: no; SelfClosing: no; FireExit: no; SecurityRating: bez
Qto_DoorBaseQuantities - Height: 2.22 m; Width: 1.29 m; Area: 2.864 m2; Perimeter: 0 m

# IfcDoor: I.DH08
In: Půdorys 1.NP
Type - PredefinedType: DOOR; ParameterTakesPrecedence: no
OverallHeight: 2.24 m; OverallWidth: 1.33 m
NEMSOK - Kód prvku: DD03.03.1208; Jednotková_cena: 0; V6: 0 m; V7: 0 m; V8: 0 m; V9: 0; Verze programu: 2.2; Označení: I.DH08; Plugin_Bezeichnung: MainObject; Plugin_Objektname: SmartPartCompressed; Uvažované procento prosklení: 100; Verze: 4.0; Podlaží: 1.NP; šířka: 1250; výška: 2100; Funkce (venkovní): Ne; Připojení EZS: Ne; Připojení NN: Ano; Připojení EPS: Ne; Připojení MaR: Ne; Připojení ACS: Ne; Typ dveřní zarážky: Bez; Typ samozavírače: bez; Vzduchová neprůzvučnost: 0; Dveře_Světlá-šířka: 0 m; Dveře_Světlá-výška: 0 m; Zárubeň/Rám_Typ: rámová; Zárubeň/Rám_Materiál: Hliníková; Zárubeň/Rám_Povrch: elox; Křídlo_Materiál: Hliníkové; Kování_Klika_Int.: loketní spínač; Kování_Klika_Ext.: loketní spínač; Kování_Zámek: bez; Specifikace: Interiérové dveře automatické posuvné dvoupanelové prosklené; Allright_Stavebni_dil_ID: 1464Obj1096214900; Jednotka: Kus; Název_objektu: Dveře - objekt+SmartPart; GlassSurface: 2.22595; HeightWindowSillOutside: 0; HeightWindowSillInside: 0; OffsetOpeningBottom: 0; OffsetOpeningTop: 0; OffsetOpeningLeft: 0; OffsetOpeningRight: 0; DeductionOpeningBottom: 100; DeductionOpeningLeft: 20; DeductionOpeningRight: 20; DeductionOpeningTop: 20
Pset_DoorCommon - Status: NEW; IsExternal: no; FireRating: EI 30DP1-Sm-C; ThermalTransmittance: 0 W/K/m2; HandicapAccessible: no; SmokeStop: no; SelfClosing: no; FireExit: no; SecurityRating: bez
Qto_DoorBaseQuantities - Height: 2.22 m; Width: 1.29 m; Area: 2.864 m2; Perimeter: 0 m

# IfcDoor: I.DH09
In: Půdorys 1.NP
Type - PredefinedType: DOOR; ParameterTakesPrecedence: no
OverallHeight: 2.24 m; OverallWidth: 1.33 m
NEMSOK - Kód prvku: DD03.03.1209; Jednotková_cena: 0; V6: 0 m; V7: 0 m; V8: 0 m; V9: 0; Verze programu: 2.2; Označení: I.DH09; Plugin_Bezeichnung: MainObject; Plugin_Objektname: SmartPartCompressed; Uvažované procento prosklení: 100; Verze: 4.0; Podlaží: 1.NP; šířka: 1250; výška: 2100; Funkce (venkovní): Ne; Připojení EZS: Ne; Připojení NN: Ano; Připojení EPS: Ne; Připojení MaR: Ne; Připojení ACS: Ne; Typ dveřní zarážky: Bez; Typ samozavírače: bez; Vzduchová neprůzvučnost: 0; Dveře_Světlá-šířka: 0 m; Dveře_Světlá-výška: 0 m; Zárubeň/Rám_Typ: rámová; Zárubeň/Rám_Materiál: Hliníková; Zárubeň/Rám_Povrch: elox; Křídlo_Materiál: Hliníkové; Kování_Klika_Int.: radar; Kování_Klika_Ext.: loketní spínač; Kování_Zámek: bez; Specifikace: Interiérové dveře automatické posuvné dvoupanelové plné; Allright_Stavebni_dil_ID: 1464Obj1096214678; Jednotka: Kus; Název_objektu: Dveře - objekt+SmartPart; GlassSurface: 2.22595; HeightWindowSillOutside: 0; HeightWindowSillInside: 0; OffsetOpeningBottom: 0; OffsetOpeningTop: 0; OffsetOpeningLeft: 0; OffsetOpeningRight: 0; DeductionOpeningBottom: 100; DeductionOpeningLeft: 20; DeductionOpeningRight: 20; DeductionOpeningTop: 20
Pset_DoorCommon - Status: NEW; IsExternal: no; ThermalTransmittance: 0 W/K/m2; HandicapAccessible: no; SmokeStop: no; SelfClosing: no; FireExit: no; SecurityRating: bez
Qto_DoorBaseQuantities - Height: 2.22 m; Width: 1.29 m; Area: 2.864 m2; Perimeter: 0 m

# IfcDoor: I.DH10
In: Půdorys 1.NP
Type - PredefinedType: DOOR; ParameterTakesPrecedence: no
OverallHeight: 2.24 m; OverallWidth: 1.58 m
NEMSOK - Kód prvku: DD03.03.1210; Jednotková_cena: 0; V6: 0 m; V7: 0 m; V8: 0 m; V9: 0; Verze programu: 2.2; Označení: I.DH10; Plugin_Bezeichnung: MainObject; Plugin_Objektname: SmartPartCompressed; Uvažované procento prosklení: 100; Verze: 4.0; Podlaží: 1.NP; šířka: 1500; výška: 2100; Funkce (venkovní): Ne; Připojení EZS: Ne; Připojení NN: Ano; Připojení EPS: Ne; Připojení MaR: Ne; Připojení ACS: Ne; Typ dveřní zarážky: Bez; Typ samozavírače: bez; Vzduchová neprůzvučnost: 0; Dveře_Světlá-šířka: 0 m; Dveře_Světlá-výška: 0 m; Zárubeň/Rám_Typ: rámová; Zárubeň/Rám_Materiál: Hliníková; Zárubeň/Rám_Povrch: elox; Křídlo_Materiál: Hliníkové; Kování_Klika_Int.: radar; Kování_Klika_Ext.: loketní spínač; Kování_Zámek: bez; Specifikace: Interiérové dveře automatické posuvné čtyřpanelové teleskopické prosklené; Allright_Stavebni_dil_ID: 1464Obj1096214232; Jednotka: Kus; Název_objektu: Dveře - objekt+SmartPart; GlassSurface: 2.3469; HeightWindowSillOutside: 0; HeightWindowSillInside: 0; OffsetOpeningBottom: 0; OffsetOpeningTop: 0; OffsetOpeningLeft: 0; OffsetOpeningRight: 0; DeductionOpeningBottom: 100; DeductionOpeningLeft: 20; DeductionOpeningRight: 20; DeductionOpeningTop: 20
Pset_DoorCommon - Status: NEW; IsExternal: no; ThermalTransmittance: 0 W/K/m2; HandicapAccessible: no; SmokeStop: no; SelfClosing: no; FireExit: no; SecurityRating: bez
Qto_DoorBaseQuantities - Height: 2.22 m; Width: 1.54 m; Area: 3.419 m2; Perimeter: 0 m

# IfcDoor: I.DH11
In: Půdorys 1.NP
Type - PredefinedType: DOOR; ParameterTakesPrecedence: no
OverallHeight: 2.24 m; OverallWidth: 1.33 m
NEMSOK - Kód prvku: DD03.03.1211; Jednotková_cena: 0; V6: 0 m; V7: 0 m; V8: 0 m; V9: 0; Verze programu: 2.2; Označení: I.DH11; Plugin_Bezeichnung: MainObject; Plugin_Objektname: SmartPartCompressed; Uvažované procento prosklení: 100; Verze: 4.0; Podlaží: 1.NP; šířka: 1250; výška: 2100; Funkce (venkovní): Ne; Připojení EZS: Ne; Připojení NN: Ano; Připojení EPS: Ne; Připojení MaR: Ne; Připojení ACS: Ne; Typ dveřní zarážky: Bez; Typ samozavírače: bez; Vzduchová neprůzvučnost: 0; Dveře_Světlá-šířka: 0 m; Dveře_Světlá-výška: 0 m; Zárubeň/Rám_Typ: rámová; Zárubeň/Rám_Materiál: Hliníková; Zárubeň/Rám_Povrch: elox; Křídlo_Materiál: Hliníkové; Kování_Klika_Int.: radar; Kování_Klika_Ext.: loketní spínač; Kování_Zámek: bez; Specifikace: Interiérové dveře automatické posuvné dvoupanelové plné; Allright_Stavebni_dil_ID: 1464Obj1096215252; Jednotka: Kus; Název_objektu: Dveře - objekt+SmartPart; GlassSurface: 2.22595; HeightWindowSillOutside: 0; HeightWindowSillInside: 0; OffsetOpeningBottom: 0; OffsetOpeningTop: 0; OffsetOpeningLeft: 0; OffsetOpeningRight: 0; DeductionOpeningBottom: 100; DeductionOpeningLeft: 20; DeductionOpeningRight: 20; DeductionOpeningTop: 20
Pset_DoorCommon - Status: NEW; IsExternal: no; ThermalTransmittance: 0 W/K/m2; HandicapAccessible: no; SmokeStop: no; SelfClosing: no; FireExit: no; SecurityRating: bez
Qto_DoorBaseQuantities - Height: 2.22 m; Width: 1.29 m; Area: 2.864 m2; Perimeter: 0 m

# IfcDoor: I.DH12
In: Půdorys 1.NP
Type - PredefinedType: DOOR; ParameterTakesPrecedence: no
OverallHeight: 2.29 m; OverallWidth: 1.58 m
NEMSOK - Kód prvku: DD03.03.1212; Jednotková_cena: 0; V6: 0 m; V7: 0 m; V8: 0 m; V9: 0; Verze programu: 2.2; Označení: I.DH12; Plugin_Bezeichnung: MainObject; Plugin_Objektname: SmartPartCompressed; Uvažované procento prosklení: 100; Verze: 4.0; Podlaží: 1.NP; šířka: 1500; výška: 2100; Funkce (venkovní): Ne; Připojení EZS: Ne; Připojení NN: Ano; Připojení EPS: Ne; Připojení MaR: Ne; Připojení ACS: Ne; Typ dveřní zarážky: Bez; Typ samozavírače: bez; Vzduchová neprůzvučnost: 0; Dveře_Světlá-šířka: 0 m; Dveře_Světlá-výška: 0 m; Zárubeň/Rám_Typ: rámová; Zárubeň/Rám_Materiál: Hliníková; Zárubeň/Rám_Povrch: elox; Křídlo_Materiál: Hliníkové; Kování_Klika_Int.: loketní spínač; Kování_Klika_Ext.: loketní spínač; Kování_Zámek: bez; Specifikace: Interiérové dveře automatické posuvné dvoupanelové prosklené; Allright_Stavebni_dil_ID: 1464Obj1096158461; Jednotka: Kus; Název_objektu: Dveře - objekt+SmartPart; GlassSurface: 2.5967; HeightWindowSillOutside: 0; HeightWindowSillInside: 0; OffsetOpeningBottom: 0; OffsetOpeningTop: 0; OffsetOpeningLeft: 0; OffsetOpeningRight: 0; DeductionOpeningBottom: 150; DeductionOpeningLeft: 20; DeductionOpeningRight: 20; DeductionOpeningTop: 20
Pset_DoorCommon - Status: NEW; IsExternal: no; FireRating: EI 30DP1-Sm-C; ThermalTransmittance: 0 W/K/m2; HandicapAccessible: no; SmokeStop: no; SelfClosing: no; FireExit: no; SecurityRating: bez
Qto_DoorBaseQuantities - Height: 2.27 m; Width: 1.54 m; Area: 3.496 m2; Perimeter: 0 m

# IfcDoor: I.DH13
In: Půdorys 1.NP
Type - PredefinedType: DOOR; ParameterTakesPrecedence: no
OverallHeight: 2.44 m; OverallWidth: 1.48 m
NEMSOK - Kód prvku: DD03.03.1213; Jednotková_cena: 0; V6: 0 m; V7: 0 m; V8: 0 m; V9: 0; Verze programu: 2.2; Označení: I.DH13; Plugin_Bezeichnung: MainObject; Plugin_Objektname: SmartPartCompressed; Uvažované procento prosklení: 100; Verze: 4.0; Podlaží: 1.NP; šířka: 1400; výška: 2100; Funkce (venkovní): Ne; Připojení EZS: Ne; Připojení NN: Ano; Připojení EPS: Ne; Připojení MaR: Ne; Připojení ACS: Ne; Typ dveřní zarážky: Bez; Typ samozavírače: bez; Vzduchová neprůzvučnost: 0; Dveře_Světlá-šířka: 0 m; Dveře_Světlá-výška: 0 m; Zárubeň/Rám_Typ: rámová; Zárubeň/Rám_Materiál: Hliníková; Zárubeň/Rám_Povrch: elox; Křídlo_Materiál: Hliníkové; Kování_Klika_Int.: loketní spínač; Kování_Klika_Ext.: loketní spínač; Kování_Zámek: bez; Specifikace: Interiérové dveře automatické posuvné jednopanelové prosklené; Allright_Stavebni_dil_ID: 1464Obj1096158486; Jednotka: Kus; Název_objektu: Dveře - objekt+SmartPart; GlassSurface: 3.0307; HeightWindowSillOutside: 0; HeightWindowSillInside: 0; OffsetOpeningBottom: 0; OffsetOpeningTop: 0; OffsetOpeningLeft: 0; OffsetOpeningRight: 0; DeductionOpeningBottom: 300; DeductionOpeningLeft: 20; DeductionOpeningRight: 20; DeductionOpeningTop: 20
Pset_DoorCommon - Status: NEW; IsExternal: no; FireRating: EI 30DP1-Sm-C; ThermalTransmittance: 0 W/K/m2; HandicapAccessible: no; SmokeStop: no; SelfClosing: no; FireExit: no; SecurityRating: bez
Qto_DoorBaseQuantities - Height: 2.42 m; Width: 1.44 m; Area: 3.485 m2; Perimeter: 0 m

# IfcDoor: I.DH14
In: Půdorys 1.NP
Type - PredefinedType: DOOR; ParameterTakesPrecedence: no
OverallHeight: 2.14 m; OverallWidth: 1.48 m
NEMSOK - Kód prvku: DD03.03.1214; Jednotková_cena: 0; V6: 0 m; V7: 0 m; V8: 0 m; V9: 0; Verze programu: 2.2; Označení: I.DH14; Plugin_Bezeichnung: MainObject; Plugin_Objektname: SmartPartCompressed; Uvažované procento prosklení: 100; Verze: 4.0; Podlaží: 1.NP; šířka: 1400; výška: 2100; Funkce (venkovní): Ne; Připojení EZS: Ne; Připojení NN: Ano; Připojení EPS: Ne; Připojení MaR: Ne; Připojení ACS: Ne; Typ dveřní zarážky: Bez; Typ samozavírače: bez; Vzduchová neprůzvučnost: 0; Dveře_Světlá-šířka: 0 m; Dveře_Světlá-výška: 0 m; Zárubeň/Rám_Typ: rámová; Zárubeň/Rám_Materiál: Hliníková; Zárubeň/Rám_Povrch: elox; Křídlo_Materiál: Hliníkové; Kování_Klika_Int.: loketní spínač; Kování_Klika_Ext.: loketní spínač; Kování_Zámek: bez; Specifikace: Interiérové dveře automatické posuvné dvoupanelové teleskopické prosklené; Allright_Stavebni_dil_ID: 1464Obj1096205268; Jednotka: Kus; Název_objektu: Dveře - objekt+SmartPart; GlassSurface: 2.398; HeightWindowSillOutside: 0; HeightWindowSillInside: 0; OffsetOpeningBottom: 0; OffsetOpeningTop: 0; OffsetOpeningLeft: 0; OffsetOpeningRight: 0; DeductionOpeningBottom: 0; DeductionOpeningLeft: 20; DeductionOpeningRight: 20; DeductionOpeningTop: 20
Pset_DoorCommon - Status: NEW; IsExternal: no; ThermalTransmittance: 0 W/K/m2; HandicapAccessible: no; SmokeStop: no; SelfClosing: no; FireExit: no; SecurityRating: bez
Qto_DoorBaseQuantities - Height: 2.12 m; Width: 1.44 m; Area: 3.053 m2; Perimeter: 0 m

# IfcDoor: I.DH15
In: Půdorys 1.NP
Type - PredefinedType: DOOR; ParameterTakesPrecedence: no
OverallHeight: 2.14 m; OverallWidth: 1.48 m
NEMSOK - Kód prvku: DD03.03.1215; Jednotková_cena: 0; V6: 0 m; V7: 0 m; V8: 0 m; V9: 0; Verze programu: 2.2; Označení: I.DH15; Plugin_Bezeichnung: MainObject; Plugin_Objektname: SmartPartCompressed; Uvažované procento prosklení: 100; Verze: 4.0; Podlaží: 1.NP; šířka: 1400; výška: 2100; Funkce (venkovní): Ne; Připojení EZS: Ne; Připojení NN: Ano; Připojení EPS: Ne; Připojení MaR: Ne; Připojení ACS: Ne; Typ dveřní zarážky: Bez; Typ samozavírače: bez; Vzduchová neprůzvučnost: 0; Dveře_Světlá-šířka: 0 m; Dveře_Světlá-výška: 0 m; Zárubeň/Rám_Typ: rámová; Zárubeň/Rám_Materiál: Hliníková; Zárubeň/Rám_Povrch: elox; Křídlo_Materiál: Hliníkové; Kování_Klika_Int.: loketní spínač; Kování_Klika_Ext.: loketní spínač; Kování_Zámek: bez; Specifikace: Interiérové dveře automatické posuvné dvoupanelové teleskopické prosklené; Allright_Stavebni_dil_ID: 1464Obj1096206029; Jednotka: Kus; Název_objektu: Dveře - objekt+SmartPart; GlassSurface: 2.398; HeightWindowSillOutside: 0; HeightWindowSillInside: 0; OffsetOpeningBottom: 0; OffsetOpeningTop: 0; OffsetOpeningLeft: 0; OffsetOpeningRight: 0; DeductionOpeningBottom: 0; DeductionOpeningLeft: 20; DeductionOpeningRight: 20; DeductionOpeningTop: 20
Pset_DoorCommon - Status: NEW; IsExternal: no; ThermalTransmittance: 0 W/K/m2; HandicapAccessible: no; SmokeStop: no; SelfClosing: no; FireExit: no; SecurityRating: bez
Qto_DoorBaseQuantities - Height: 2.12 m; Width: 1.44 m; Area: 3.053 m2; Perimeter: 0 m

# IfcDoor: I.DH16
In: Půdorys 1.NP
Type - PredefinedType: DOOR; ParameterTakesPrecedence: no
OverallHeight: 2.14 m; OverallWidth: 1.48 m
NEMSOK - Kód prvku: DD03.03.1216; Jednotková_cena: 0; V6: 0 m; V7: 0 m; V8: 0 m; V9: 0; Verze programu: 2.2; Označení: I.DH16; Plugin_Bezeichnung: MainObject; Plugin_Objektname: SmartPartCompressed; Uvažované procento prosklení: 100; Verze: 4.0; Podlaží: 1.NP; šířka: 1400; výška: 2100; Funkce (venkovní): Ne; Připojení EZS: Ne; Připojení NN: Ano; Připojení EPS: Ne; Připojení MaR: Ne; Připojení ACS: Ne; Typ dveřní zarážky: Bez; Typ samozavírače: bez; Vzduchová neprůzvučnost: 0; Dveře_Světlá-šířka: 0 m; Dveře_Světlá-výška: 0 m; Zárubeň/Rám_Typ: rámová; Zárubeň/Rám_Materiál: Hliníková; Zárubeň/Rám_Povrch: elox; Křídlo_Materiál: Hliníkové; Kování_Klika_Int.: loketní spínač; Kování_Klika_Ext.: loketní spínač; Kování_Zámek: bez; Specifikace: Interiérové dveře automatické posuvné dvoupanelové teleskopické prosklené; Allright_Stavebni_dil_ID: 1464Obj1096205830; Jednotka: Kus; Název_objektu: Dveře - objekt+SmartPart; GlassSurface: 2.398; HeightWindowSillOutside: 0; HeightWindowSillInside: 0; OffsetOpeningBottom: 0; OffsetOpeningTop: 0; OffsetOpeningLeft: 0; OffsetOpeningRight: 0; DeductionOpeningBottom: 0; DeductionOpeningLeft: 20; DeductionOpeningRight: 20; DeductionOpeningTop: 20
Pset_DoorCommon - Status: NEW; IsExternal: no; ThermalTransmittance: 0 W/K/m2; HandicapAccessible: no; SmokeStop: no; SelfClosing: no; FireExit: no; SecurityRating: bez
Qto_DoorBaseQuantities - Height: 2.12 m; Width: 1.44 m; Area: 3.053 m2; Perimeter: 0 m

# IfcDoor: I.DH17
In: Půdorys 1.NP
Type - PredefinedType: DOOR; ParameterTakesPrecedence: no
OverallHeight: 2.14 m; OverallWidth: 1.48 m
NEMSOK - Kód prvku: DD03.03.1217; Jednotková_cena: 0; V6: 0 m; V7: 0 m; V8: 0 m; V9: 0; Verze programu: 2.2; Označení: I.DH17; Plugin_Bezeichnung: MainObject; Plugin_Objektname: SmartPartCompressed; Uvažované procento prosklení: 100; Verze: 4.0; Podlaží: 1.NP; šířka: 1400; výška: 2100; Funkce (venkovní): Ne; Připojení EZS: Ne; Připojení NN: Ano; Připojení EPS: Ne; Připojení MaR: Ne; Připojení ACS: Ne; Typ dveřní zarážky: Bez; Typ samozavírače: bez; Vzduchová neprůzvučnost: 0; Dveře_Světlá-šířka: 0 m; Dveře_Světlá-výška: 0 m; Zárubeň/Rám_Typ: rámová; Zárubeň/Rám_Materiál: Hliníková; Zárubeň/Rám_Povrch: elox; Křídlo_Materiál: Hliníkové; Kování_Klika_Int.: loketní spínač; Kování_Klika_Ext.: loketní spínač; Kování_Zámek: bez; Specifikace: Interiérové dveře automatické posuvné dvoupanelové teleskopické prosklené; Allright_Stavebni_dil_ID: 1464Obj1096205779; Jednotka: Kus; Název_objektu: Dveře - objekt+SmartPart; GlassSurface: 2.398; HeightWindowSillOutside: 0; HeightWindowSillInside: 0; OffsetOpeningBottom: 0; OffsetOpeningTop: 0; OffsetOpeningLeft: 0; OffsetOpeningRight: 0; DeductionOpeningBottom: 0; DeductionOpeningLeft: 20; DeductionOpeningRight: 20; DeductionOpeningTop: 20
Pset_DoorCommon - Status: NEW; IsExternal: no; ThermalTransmittance: 0 W/K/m2; HandicapAccessible: no; SmokeStop: no; SelfClosing: no; FireExit: no; SecurityRating: bez
Qto_DoorBaseQuantities - Height: 2.12 m; Width: 1.44 m; Area: 3.053 m2; Perimeter: 0 m

# IfcDoor: I.DH18
In: Půdorys 1.NP
Type - PredefinedType: DOOR; ParameterTakesPrecedence: no
OverallHeight: 2.14 m; OverallWidth: 1.48 m
NEMSOK - Kód prvku: DD03.03.1218; Jednotková_cena: 0; V6: 0 m; V7: 0 m; V8: 0 m; V9: 0; Verze programu: 2.2; Označení: I.DH18; Plugin_Bezeichnung: MainObject; Plugin_Objektname: SmartPartCompressed; Uvažované procento prosklení: 100; Verze: 4.0; Podlaží: 1.NP; šířka: 1400; výška: 2100; Funkce (venkovní): Ne; Připojení EZS: Ne; Připojení NN: Ano; Připojení EPS: Ne; Připojení MaR: Ne; Připojení ACS: Ne; Typ dveřní zarážky: Bez; Typ samozavírače: bez; Vzduchová neprůzvučnost: 0; Dveře_Světlá-šířka: 0 m; Dveře_Světlá-výška: 0 m; Zárubeň/Rám_Typ: rámová; Zárubeň/Rám_Materiál: Hliníková; Zárubeň/Rám_Povrch: elox; Křídlo_Materiál: Hliníkové; Kování_Klika_Int.: loketní spínač; Kování_Klika_Ext.: loketní spínač; Kování_Zámek: bez; Specifikace: Interiérové dveře automatické posuvné dvoupanelové teleskopické prosklené; Allright_Stavebni_dil_ID: 1464Obj1096205652; Jednotka: Kus; Název_objektu: Dveře - objekt+SmartPart; GlassSurface: 2.398; HeightWindowSillOutside: 0; HeightWindowSillInside: 0; OffsetOpeningBottom: 0; OffsetOpeningTop: 0; OffsetOpeningLeft: 0; OffsetOpeningRight: 0; DeductionOpeningBottom: 0; DeductionOpeningLeft: 20; DeductionOpeningRight: 20; DeductionOpeningTop: 20
Pset_DoorCommon - Status: NEW; IsExternal: no; ThermalTransmittance: 0 W/K/m2; HandicapAccessible: no; SmokeStop: no; SelfClosing: no; FireExit: no; SecurityRating: bez
Qto_DoorBaseQuantities - Height: 2.12 m; Width: 1.44 m; Area: 3.053 m2; Perimeter: 0 m

# IfcDoor: I.DH19
In: Půdorys 1.NP
Type - PredefinedType: DOOR; ParameterTakesPrecedence: no
OverallHeight: 2.14 m; OverallWidth: 1.48 m
NEMSOK - Kód prvku: DD03.03.1219; Jednotková_cena: 0; V6: 0 m; V7: 0 m; V8: 0 m; V9: 0; Verze programu: 2.2; Označení: I.DH19; Plugin_Bezeichnung: MainObject; Plugin_Objektname: SmartPartCompressed; Uvažované procento prosklení: 100; Verze: 4.0; Podlaží: 1.NP; šířka: 1400; výška: 2100; Funkce (venkovní): Ne; Připojení EZS: Ne; Připojení NN: Ano; Připojení EPS: Ne; Připojení MaR: Ne; Připojení ACS: Ne; Typ dveřní zarážky: Bez; Typ samozavírače: bez; Vzduchová neprůzvučnost: 0; Dveře_Světlá-šířka: 0 m; Dveře_Světlá-výška: 0 m; Zárubeň/Rám_Typ: rámová; Zárubeň/Rám_Materiál: Hliníková; Zárubeň/Rám_Povrch: elox; Křídlo_Materiál: Hliníkové; Kování_Klika_Int.: loketní spínač; Kování_Klika_Ext.: loketní spínač; Kování_Zámek: bez; Specifikace: Interiérové dveře automatické posuvné dvoupanelové teleskopické prosklené; Allright_Stavebni_dil_ID: 1464Obj1096158258; Jednotka: Kus; Název_objektu: Dveře - objekt+SmartPart; GlassSurface: 2.398; HeightWindowSillOutside: 0; HeightWindowSillInside: 0; OffsetOpeningBottom: 0; OffsetOpeningTop: 0; OffsetOpeningLeft: 0; OffsetOpeningRight: 0; DeductionOpeningBottom: 0; DeductionOpeningLeft: 20; DeductionOpeningRight: 20; DeductionOpeningTop: 20
Pset_DoorCommon - Status: NEW; IsExternal: no; ThermalTransmittance: 0 W/K/m2; HandicapAccessible: no; SmokeStop: no; SelfClosing: no; FireExit: no; SecurityRating: bez
Qto_DoorBaseQuantities - Height: 2.12 m; Width: 1.44 m; Area: 3.053 m2; Perimeter: 0 m

# IfcDoor: I.DH20
In: Půdorys 1.NP
Type - PredefinedType: DOOR; ParameterTakesPrecedence: no
OverallHeight: 2.1 m; OverallWidth: 1.5 m
NEMSOK - Kód prvku: DD03.03.1220; Jednotková_cena: 0; V6: 0 m; V7: 0 m; V8: 0 m; V9: 0; Verze programu: 2.2; Označení: I.DH20; Plugin_Bezeichnung: MainObject; Plugin_Objektname: SmartPartCompressed; Uvažované procento prosklení: 100; Verze: 4.0; Podlaží: 1.NP; šířka: 1400; výška: 2050; Funkce (venkovní): Ne; Připojení EZS: Ne; Připojení NN: Ano; Připojení EPS: Ne; Připojení MaR: Ne; Připojení ACS: Ne; Typ dveřní zarážky: Bez; Typ samozavírače: bez; Vzduchová neprůzvučnost: 0; Dveře_Světlá-šířka: 0 m; Dveře_Světlá-výška: 0 m; Zárubeň/Rám_Typ: rámová; Zárubeň/Rám_Materiál: Hliníková; Zárubeň/Rám_Povrch: elox; Křídlo_Materiál: Hliníkové; Kování_Klika_Int.: loketní spínač; Kování_Klika_Ext.: loketní spínač; Kování_Zámek: bez; Specifikace: Interiérové dveře automatické dvoukřídlové prosklené; Allright_Stavebni_dil_ID: 1464Obj1096158283; Jednotka: Kus; Název_objektu: Dveře - objekt+SmartPart; GlassSurface: 2.33805; HeightWindowSillOutside: 0; HeightWindowSillInside: 0; OffsetOpeningBottom: 0; OffsetOpeningTop: 0; OffsetOpeningLeft: 0; OffsetOpeningRight: 0; DeductionOpeningBottom: 0; DeductionOpeningLeft: 50; DeductionOpeningRight: 50; DeductionOpeningTop: 50
Pset_DoorCommon - Status: NEW; IsExternal: no; ThermalTransmittance: 0 W/K/m2; HandicapAccessible: no; SmokeStop: no; SelfClosing: no; FireExit: no; SecurityRating: bez
Qto_DoorBaseQuantities - Height: 2.1 m; Width: 1.5 m; Area: 3.15 m2; Perimeter: 0 m

# IfcDoor: I.DH21
In: Půdorys 1.NP
Type - PredefinedType: DOOR; ParameterTakesPrecedence: no
OverallHeight: 2.34 m; OverallWidth: 1.48 m
NEMSOK - Kód prvku: DD03.03.1221; Jednotková_cena: 0; V6: 0 m; V7: 0 m; V8: 0 m; V9: 0; Verze programu: 2.2; Označení: I.DH21; Plugin_Bezeichnung: MainObject; Plugin_Objektname: SmartPartCompressed; Uvažované procento prosklení: 100; Verze: 4.0; Podlaží: 1.NP; šířka: 1400; výška: 2200; Funkce (venkovní): Ne; Připojení EZS: Ne; Připojení NN: Ano; Připojení EPS: Ne; Připojení MaR: Ne; Připojení ACS: Ano; Typ dveřní zarážky: Bez; Typ samozavírače: bez; Vzduchová neprůzvučnost: 0; Dveře_Světlá-šířka: 0 m; Dveře_Světlá-výška: 0 m; Zárubeň/Rám_Typ: rámová; Zárubeň/Rám_Materiál: Hliníková; Zárubeň/Rám_Povrch: elox; Křídlo_Materiál: Hliníkové; Kování_Klika_Int.: radar; Kování_Klika_Ext.: čtečka karet; Kování_Zámek: bez; Specifikace: Interiérové dveře automatické posuvné jednopanelové prosklené; Allright_Stavebni_dil_ID: 1464Obj1096209024; Jednotka: Kus; Název_objektu: Dveře - objekt+SmartPart; GlassSurface: 2.8727; HeightWindowSillOutside: 0; HeightWindowSillInside: 0; OffsetOpeningBottom: 0; OffsetOpeningTop: 0; OffsetOpeningLeft: 0; OffsetOpeningRight: 0; DeductionOpeningBottom: 100; DeductionOpeningLeft: 20; DeductionOpeningRight: 20; DeductionOpeningTop: 20
Pset_DoorCommon - Status: NEW; IsExternal: no; FireRating: EW 30DP1-C; ThermalTransmittance: 0 W/K/m2; HandicapAccessible: no; SmokeStop: no; SelfClosing: no; FireExit: no; SecurityRating: bez
Qto_DoorBaseQuantities - Height: 2.32 m; Width: 1.44 m; Area: 3.341 m2; Perimeter: 0 m

# IfcDoor: I.DHP01
In: Půdorys 1.NP
Type - PredefinedType: DOOR; ParameterTakesPrecedence: no
OverallHeight: 2.14 m; OverallWidth: 0.98 m
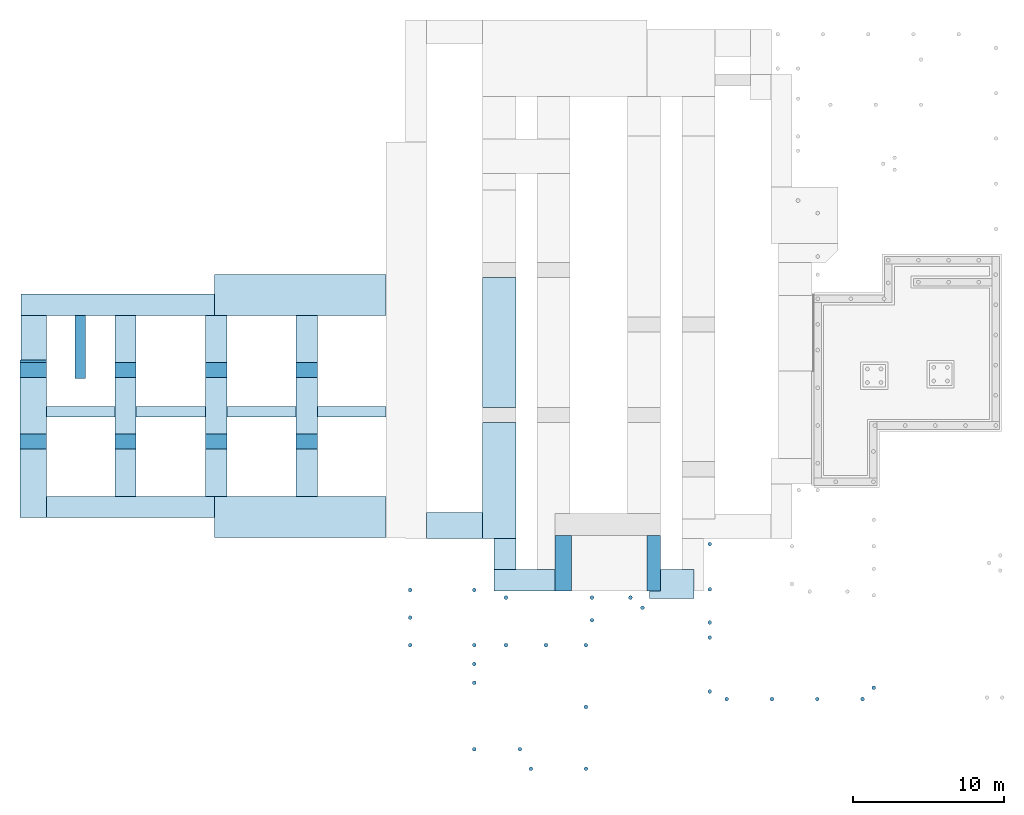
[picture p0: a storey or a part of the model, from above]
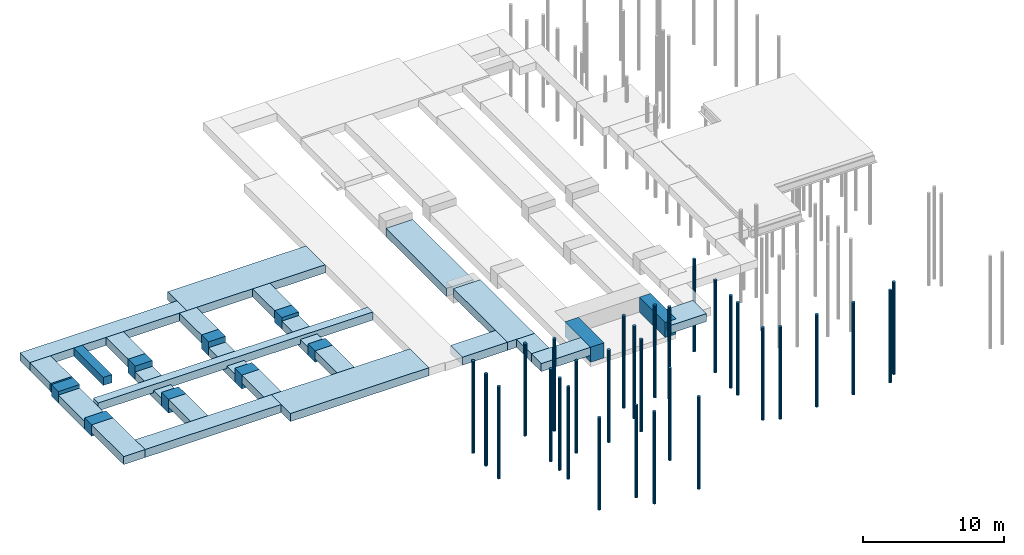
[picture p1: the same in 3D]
Properties of the parts of a building model (IFC4), part 11 of 45

# IfcDoor: I.DHP01
NEMSOK - Kód prvku: DD03.03.1301; Jednotková_cena: 0; V6: 0 m; V7: 0 m; V8: 0 m; V9: 0; Verze programu: 2.2; Označení: I.DHP01; Plugin_Bezeichnung: MainObject; Plugin_Objektname: SmartPartCompressed; Uvažované procento prosklení: 100; Verze: 4.0; Podlaží: 1.NP; šířka: 900; výška: 2100; Funkce (venkovní): Ne; Připojení EZS: Ne; Připojení NN: Ne; Připojení EPS: Ne; Připojení MaR: Ne; Připojení ACS: Ne; Typ dveřní zarážky: Bez; Typ samozavírače: bez; Vzduchová neprůzvučnost: 0; Dveře_Světlá-šířka: 0 m; Dveře_Světlá-výška: 0 m; Zárubeň/Rám_Typ: rámová; Zárubeň/Rám_Materiál: Hliníková; Zárubeň/Rám_Povrch: elox; Křídlo_Materiál: Hliníkové; Kování_Klika_Int.: madlo; Kování_Klika_Ext.: madlo; Kování_Zámek: bez; Specifikace: Interiérové dveře posuvné jednopanelové prosklené; Allright_Stavebni_dil_ID: 1464Obj1096207011; Jednotka: Kus; Název_objektu: Dveře - objekt+SmartPart; GlassSurface: 1.33; HeightWindowSillOutside: 0; HeightWindowSillInside: 0; OffsetOpeningBottom: 0; OffsetOpeningTop: 0; OffsetOpeningLeft: 0; OffsetOpeningRight: 0; DeductionOpeningBottom: 0; DeductionOpeningLeft: 20; DeductionOpeningRight: 20; DeductionOpeningTop: 20
Pset_DoorCommon - Status: NEW; IsExternal: no; ThermalTransmittance: 0 W/K/m2; HandicapAccessible: no; SmokeStop: no; SelfClosing: no; FireExit: no; SecurityRating: bez
Qto_DoorBaseQuantities - Height: 2.12 m; Width: 0.94 m; Area: 1.993 m2; Perimeter: 0 m

# IfcDoor: I.DHP02
In: Půdorys 1.NP
Type - PredefinedType: DOOR; ParameterTakesPrecedence: no
OverallHeight: 2.14 m; OverallWidth: 0.98 m
NEMSOK - Kód prvku: DD03.03.1302; Jednotková_cena: 0; V6: 0 m; V7: 0 m; V8: 0 m; V9: 0; Verze programu: 2.2; Označení: I.DHP02; Plugin_Bezeichnung: MainObject; Plugin_Objektname: SmartPartCompressed; Uvažované procento prosklení: 100; Verze: 4.0; Podlaží: 1.NP; šířka: 900; výška: 2100; Funkce (venkovní): Ne; Připojení EZS: Ne; Připojení NN: Ne; Připojení EPS: Ne; Připojení MaR: Ne; Připojení ACS: Ne; Typ dveřní zarážky: Bez; Typ samozavírače: bez; Vzduchová neprůzvučnost: 0; Dveře_Světlá-šířka: 0 m; Dveře_Světlá-výška: 0 m; Zárubeň/Rám_Typ: rámová; Zárubeň/Rám_Materiál: Hliníková; Zárubeň/Rám_Povrch: elox; Křídlo_Materiál: Hliníkové; Kování_Klika_Int.: madlo; Kování_Klika_Ext.: madlo; Kování_Zámek: bez; Specifikace: Interiérové dveře posuvné jednopanelové prosklené; Allright_Stavebni_dil_ID: 1464Obj1096207173; Jednotka: Kus; Název_objektu: Dveře - objekt+SmartPart; GlassSurface: 1.33; HeightWindowSillOutside: 0; HeightWindowSillInside: 0; OffsetOpeningBottom: 0; OffsetOpeningTop: 0; OffsetOpeningLeft: 0; OffsetOpeningRight: 0; DeductionOpeningBottom: 0; DeductionOpeningLeft: 20; DeductionOpeningRight: 20; DeductionOpeningTop: 20
Pset_DoorCommon - Status: NEW; IsExternal: no; ThermalTransmittance: 0 W/K/m2; HandicapAccessible: no; SmokeStop: no; SelfClosing: no; FireExit: no; SecurityRating: bez
Qto_DoorBaseQuantities - Height: 2.12 m; Width: 0.94 m; Area: 1.993 m2; Perimeter: 0 m

# IfcDoor: I.DHP03
In: Půdorys 1.NP
Type - PredefinedType: DOOR; ParameterTakesPrecedence: no
OverallHeight: 2.14 m; OverallWidth: 0.98 m
NEMSOK - Kód prvku: DD03.03.1303; Jednotková_cena: 0; V6: 0 m; V7: 0 m; V8: 0 m; V9: 0; Verze programu: 2.2; Označení: I.DHP03; Plugin_Bezeichnung: MainObject; Plugin_Objektname: SmartPartCompressed; Uvažované procento prosklení: 100; Verze: 4.0; Podlaží: 1.NP; šířka: 900; výška: 2100; Funkce (venkovní): Ne; Připojení EZS: Ne; Připojení NN: Ne; Připojení EPS: Ne; Připojení MaR: Ne; Připojení ACS: Ne; Typ dveřní zarážky: Bez; Typ samozavírače: bez; Vzduchová neprůzvučnost: 0; Dveře_Světlá-šířka: 0 m; Dveře_Světlá-výška: 0 m; Zárubeň/Rám_Typ: rámová; Zárubeň/Rám_Materiál: Hliníková; Zárubeň/Rám_Povrch: elox; Křídlo_Materiál: Hliníkové; Kování_Klika_Int.: madlo; Kování_Klika_Ext.: madlo; Kování_Zámek: bez; Specifikace: Interiérové dveře posuvné jednopanelové prosklené; Allright_Stavebni_dil_ID: 1464Obj1096207254; Jednotka: Kus; Název_objektu: Dveře - objekt+SmartPart; GlassSurface: 1.33; HeightWindowSillOutside: 0; HeightWindowSillInside: 0; OffsetOpeningBottom: 0; OffsetOpeningTop: 0; OffsetOpeningLeft: 0; OffsetOpeningRight: 0; DeductionOpeningBottom: 0; DeductionOpeningLeft: 20; DeductionOpeningRight: 20; DeductionOpeningTop: 20
Pset_DoorCommon - Status: NEW; IsExternal: no; ThermalTransmittance: 0 W/K/m2; HandicapAccessible: no; SmokeStop: no; SelfClosing: no; FireExit: no; SecurityRating: bez
Qto_DoorBaseQuantities - Height: 2.12 m; Width: 0.94 m; Area: 1.993 m2; Perimeter: 0 m

# IfcDoor: I.DHP04
In: Půdorys 1.NP
Type - PredefinedType: DOOR; ParameterTakesPrecedence: no
OverallHeight: 2.14 m; OverallWidth: 0.98 m
NEMSOK - Kód prvku: DD03.03.1304; Jednotková_cena: 0; V6: 0 m; V7: 0 m; V8: 0 m; V9: 0; Verze programu: 2.2; Označení: I.DHP04; Plugin_Bezeichnung: MainObject; Plugin_Objektname: SmartPartCompressed; Uvažované procento prosklení: 100; Verze: 4.0; Podlaží: 1.NP; šířka: 900; výška: 2100; Funkce (venkovní): Ne; Připojení EZS: Ne; Připojení NN: Ne; Připojení EPS: Ne; Připojení MaR: Ne; Připojení ACS: Ne; Typ dveřní zarážky: Bez; Typ samozavírače: bez; Vzduchová neprůzvučnost: 0; Dveře_Světlá-šířka: 0 m; Dveře_Světlá-výška: 0 m; Zárubeň/Rám_Typ: rámová; Zárubeň/Rám_Materiál: Hliníková; Zárubeň/Rám_Povrch: elox; Křídlo_Materiál: Hliníkové; Kování_Klika_Int.: madlo; Kování_Klika_Ext.: madlo; Kování_Zámek: bez; Specifikace: Interiérové dveře posuvné jednopanelové prosklené; Allright_Stavebni_dil_ID: 1464Obj1096207336; Jednotka: Kus; Název_objektu: Dveře - objekt+SmartPart; GlassSurface: 1.33; HeightWindowSillOutside: 0; HeightWindowSillInside: 0; OffsetOpeningBottom: 0; OffsetOpeningTop: 0; OffsetOpeningLeft: 0; OffsetOpeningRight: 0; DeductionOpeningBottom: 0; DeductionOpeningLeft: 20; DeductionOpeningRight: 20; DeductionOpeningTop: 20
Pset_DoorCommon - Status: NEW; IsExternal: no; ThermalTransmittance: 0 W/K/m2; HandicapAccessible: no; SmokeStop: no; SelfClosing: no; FireExit: no; SecurityRating: bez
Qto_DoorBaseQuantities - Height: 2.12 m; Width: 0.94 m; Area: 1.993 m2; Perimeter: 0 m

# IfcDoor: I.DP01
In: Půdorys 1.NP
Type - PredefinedType: DOOR; ParameterTakesPrecedence: no
OverallHeight: 2.16 m; OverallWidth: 1.745 m
NEMSOK - Kód prvku: DD01.03.1001; Jednotková_cena: 0; V6: 0 m; V7: 0 m; V8: 0 m; V9: 0; Verze programu: 2.2; Označení: I.DP01; Plugin_Bezeichnung: MainObject; Plugin_Objektname: SmartPartCompressed; Uvažované procento prosklení: 100; Verze: 4.0; Podlaží: 1.NP; šířka: 700; výška: 1970; Funkce (venkovní): Ne; Připojení EZS: Ne; Připojení NN: Ne; Připojení EPS: Ne; Připojení MaR: Ne; Připojení ACS: Ne; Typ dveřní zarážky: Bez; Typ samozavírače: bez; Vzduchová neprůzvučnost: 0; Dveře_Světlá-šířka: 0 m; Dveře_Světlá-výška: 0 m; Zárubeň/Rám_Typ: dvoudílná; Zárubeň/Rám_Materiál: Ocelová; Zárubeň/Rám_Povrch: komaxit; Křídlo_Materiál: Dřevěné; Křídlo_Povrch_Int.: HPL laminát; Křídlo_Povrch_Ext.: HPL laminát; Kování_Klika_Int.: madlo; Kování_Klika_Ext.: madlo; Kování_Zámek: WC zámek; Specifikace: Interiérové dveře jednokřídlé plné posuvné do SDK; Allright_Stavebni_dil_ID: 1464Obj1096313271; Jednotka: Kus; Název_objektu: Dveře - objekt+SmartPart; GlassSurface: 0.1745; HeightWindowSillOutside: 0; HeightWindowSillInside: 0; OffsetOpeningBottom: 0; OffsetOpeningTop: 0; OffsetOpeningLeft: 0; OffsetOpeningRight: 0; DeductionOpeningBottom: 100; DeductionOpeningLeft: 995; DeductionOpeningRight: 50; DeductionOpeningTop: 90
Pset_DoorCommon - Status: NEW; IsExternal: no; ThermalTransmittance: 0 W/K/m2; HandicapAccessible: no; SmokeStop: no; SelfClosing: no; FireExit: no; SecurityRating: bez
Qto_DoorBaseQuantities - Height: 2.16 m; Width: 1.745 m; Area: 3.769 m2; Perimeter: 0 m

# IfcDoor: I.DP02
In: Půdorys 1.NP
Type - PredefinedType: DOOR; ParameterTakesPrecedence: no
OverallHeight: 2.16 m; OverallWidth: 1.745 m
NEMSOK - Kód prvku: DD01.03.1002; Jednotková_cena: 0; V6: 0 m; V7: 0 m; V8: 0 m; V9: 0; Verze programu: 2.2; Označení: I.DP02; Plugin_Bezeichnung: MainObject; Plugin_Objektname: SmartPartCompressed; Uvažované procento prosklení: 100; Verze: 4.0; Podlaží: 1.NP; šířka: 700; výška: 1970; Funkce (venkovní): Ne; Připojení EZS: Ne; Připojení NN: Ne; Připojení EPS: Ne; Připojení MaR: Ne; Připojení ACS: Ne; Typ dveřní zarážky: Bez; Typ samozavírače: bez; Vzduchová neprůzvučnost: 0; Dveře_Světlá-šířka: 0 m; Dveře_Světlá-výška: 0 m; Zárubeň/Rám_Typ: dvoudílná; Zárubeň/Rám_Materiál: Ocelová; Zárubeň/Rám_Povrch: komaxit; Křídlo_Materiál: Dřevěné; Křídlo_Povrch_Int.: HPL laminát; Křídlo_Povrch_Ext.: HPL laminát; Kování_Klika_Int.: madlo; Kování_Klika_Ext.: madlo; Kování_Zámek: mechanický vložkový; Specifikace: Interiérové dveře jednokřídlé plné posuvné do SDK; Allright_Stavebni_dil_ID: 1464Obj1096313282; Jednotka: Kus; Název_objektu: Dveře - objekt+SmartPart; GlassSurface: 0.1745; HeightWindowSillOutside: 0; HeightWindowSillInside: 0; OffsetOpeningBottom: 0; OffsetOpeningTop: 0; OffsetOpeningLeft: 0; OffsetOpeningRight: 0; DeductionOpeningBottom: 100; DeductionOpeningLeft: 995; DeductionOpeningRight: 50; DeductionOpeningTop: 90
Pset_DoorCommon - Status: NEW; IsExternal: no; ThermalTransmittance: 0 W/K/m2; HandicapAccessible: no; SmokeStop: no; SelfClosing: no; FireExit: no; SecurityRating: bez
Qto_DoorBaseQuantities - Height: 2.16 m; Width: 1.745 m; Area: 3.769 m2; Perimeter: 0 m

# IfcDoor: I.DP03
In: Půdorys 1.NP
Type - PredefinedType: DOOR; ParameterTakesPrecedence: no
OverallHeight: 2.16 m; OverallWidth: 1.945 m
NEMSOK - Kód prvku: DD01.03.1003; Jednotková_cena: 0; V6: 0 m; V7: 0 m; V8: 0 m; V9: 0; Verze programu: 2.2; Označení: I.DP03; Plugin_Bezeichnung: MainObject; Plugin_Objektname: SmartPartCompressed; Uvažované procento prosklení: 100; Verze: 4.0; Podlaží: 1.NP; šířka: 900; výška: 1970; Funkce (venkovní): Ne; Připojení EZS: Ne; Připojení NN: Ne; Připojení EPS: Ne; Připojení MaR: Ne; Připojení ACS: Ne; Typ dveřní zarážky: Bez; Typ samozavírače: bez; Vzduchová neprůzvučnost: 0; Dveře_Světlá-šířka: 0 m; Dveře_Světlá-výška: 0 m; Zárubeň/Rám_Typ: dvoudílná; Zárubeň/Rám_Materiál: Ocelová; Zárubeň/Rám_Povrch: komaxit; Křídlo_Materiál: Dřevěné; Křídlo_Povrch_Int.: HPL laminát; Křídlo_Povrch_Ext.: HPL laminát; Kování_Klika_Int.: madlo; Kování_Klika_Ext.: madlo; Kování_Zámek: WC zámek; Specifikace: Interiérové dveře jednokřídlé plné posuvné do SDK; Allright_Stavebni_dil_ID: 1464Obj1096313113; Jednotka: Kus; Název_objektu: Dveře - objekt+SmartPart; GlassSurface: 0.1945; HeightWindowSillOutside: 0; HeightWindowSillInside: 0; OffsetOpeningBottom: 0; OffsetOpeningTop: 0; OffsetOpeningLeft: 0; OffsetOpeningRight: 0; DeductionOpeningBottom: 100; DeductionOpeningLeft: 995; DeductionOpeningRight: 50; DeductionOpeningTop: 90
Pset_DoorCommon - Status: NEW; IsExternal: no; ThermalTransmittance: 0 W/K/m2; HandicapAccessible: no; SmokeStop: no; SelfClosing: no; FireExit: no; SecurityRating: bez
Qto_DoorBaseQuantities - Height: 2.16 m; Width: 1.945 m; Area: 4.201 m2; Perimeter: 0 m

# IfcDoor: I.DP04
In: Půdorys 1.NP
Type - PredefinedType: DOOR; ParameterTakesPrecedence: no
OverallHeight: 2.16 m; OverallWidth: 1.945 m
NEMSOK - Kód prvku: DD01.03.1004; Jednotková_cena: 0; V6: 0 m; V7: 0 m; V8: 0 m; V9: 0; Verze programu: 2.2; Označení: I.DP04; Plugin_Bezeichnung: MainObject; Plugin_Objektname: SmartPartCompressed; Uvažované procento prosklení: 100; Verze: 4.0; Podlaží: 1.NP; šířka: 900; výška: 1970; Funkce (venkovní): Ne; Připojení EZS: Ne; Připojení NN: Ne; Připojení EPS: Ne; Připojení MaR: Ne; Připojení ACS: Ne; Typ dveřní zarážky: Bez; Typ samozavírače: bez; Vzduchová neprůzvučnost: 0; Dveře_Světlá-šířka: 0 m; Dveře_Světlá-výška: 0 m; Zárubeň/Rám_Typ: dvoudílná; Zárubeň/Rám_Materiál: Ocelová; Zárubeň/Rám_Povrch: komaxit; Křídlo_Materiál: Dřevěné; Křídlo_Povrch_Int.: HPL laminát; Křídlo_Povrch_Ext.: HPL laminát; Kování_Klika_Int.: madlo; Kování_Klika_Ext.: madlo; Kování_Zámek: WC zámek; Specifikace: Interiérové dveře jednokřídlé plné posuvné do SDK; Allright_Stavebni_dil_ID: 1464Obj1096313108; Jednotka: Kus; Název_objektu: Dveře - objekt+SmartPart; GlassSurface: 0.1945; HeightWindowSillOutside: 0; HeightWindowSillInside: 0; OffsetOpeningBottom: 0; OffsetOpeningTop: 0; OffsetOpeningLeft: 0; OffsetOpeningRight: 0; DeductionOpeningBottom: 100; DeductionOpeningLeft: 995; DeductionOpeningRight: 50; DeductionOpeningTop: 90
Pset_DoorCommon - Status: NEW; IsExternal: no; ThermalTransmittance: 0 W/K/m2; HandicapAccessible: no; SmokeStop: no; SelfClosing: no; FireExit: no; SecurityRating: bez
Qto_DoorBaseQuantities - Height: 2.16 m; Width: 1.945 m; Area: 4.201 m2; Perimeter: 0 m

# IfcDoor: I.DP05
In: Půdorys 1.NP
Type - PredefinedType: DOOR; ParameterTakesPrecedence: no
OverallHeight: 2.16 m; OverallWidth: 1.945 m
NEMSOK - Kód prvku: DD01.03.1005; Jednotková_cena: 0; V6: 0 m; V7: 0 m; V8: 0 m; V9: 0; Verze programu: 2.2; Označení: I.DP05; Plugin_Bezeichnung: MainObject; Plugin_Objektname: SmartPartCompressed; Uvažované procento prosklení: 100; Verze: 4.0; Podlaží: 1.NP; šířka: 900; výška: 1970; Funkce (venkovní): Ne; Připojení EZS: Ne; Připojení NN: Ne; Připojení EPS: Ne; Připojení MaR: Ne; Připojení ACS: Ne; Typ dveřní zarážky: Bez; Typ samozavírače: bez; Vzduchová neprůzvučnost: 0; Dveře_Světlá-šířka: 0 m; Dveře_Světlá-výška: 0 m; Zárubeň/Rám_Typ: dvoudílná; Zárubeň/Rám_Materiál: Ocelová; Zárubeň/Rám_Povrch: komaxit; Křídlo_Materiál: Dřevěné; Křídlo_Povrch_Int.: HPL laminát; Křídlo_Povrch_Ext.: HPL laminát; Kování_Klika_Int.: madlo; Kování_Klika_Ext.: madlo; Kování_Zámek: mechanický vložkový; Specifikace: Interiérové dveře jednokřídlé plné posuvné do SDK; Allright_Stavebni_dil_ID: 1464Obj1096313079; Jednotka: Kus; Název_objektu: Dveře - objekt+SmartPart; GlassSurface: 0.1945; HeightWindowSillOutside: 0; HeightWindowSillInside: 0; OffsetOpeningBottom: 0; OffsetOpeningTop: 0; OffsetOpeningLeft: 0; OffsetOpeningRight: 0; DeductionOpeningBottom: 100; DeductionOpeningLeft: 995; DeductionOpeningRight: 50; DeductionOpeningTop: 90
Pset_DoorCommon - Status: NEW; IsExternal: no; ThermalTransmittance: 0 W/K/m2; HandicapAccessible: no; SmokeStop: no; SelfClosing: no; FireExit: no; SecurityRating: bez
Qto_DoorBaseQuantities - Height: 2.16 m; Width: 1.945 m; Area: 4.201 m2; Perimeter: 0 m

# IfcDoor: I.DP06
In: Půdorys 1.NP
Type - PredefinedType: DOOR; ParameterTakesPrecedence: no
OverallHeight: 2.06 m; OverallWidth: 1.545 m
NEMSOK - Kód prvku: DD01.03.1006; Jednotková_cena: 0; V6: 0 m; V7: 0 m; V8: 0 m; V9: 0; Verze programu: 2.2; Označení: I.DP06; Plugin_Bezeichnung: MainObject; Plugin_Objektname: SmartPartCompressed; Uvažované procento prosklení: 100; Verze: 4.0; Podlaží: 1.NP; šířka: 700; výška: 1970; Funkce (venkovní): Ne; Připojení EZS: Ne; Připojení NN: Ne; Připojení EPS: Ne; Připojení MaR: Ne; Připojení ACS: Ne; Typ dveřní zarážky: Bez; Typ samozavírače: bez; Vzduchová neprůzvučnost: 0; Dveře_Světlá-šířka: 0 m; Dveře_Světlá-výška: 0 m; Zárubeň/Rám_Typ: dvoudílná; Zárubeň/Rám_Materiál: Ocelová; Zárubeň/Rám_Povrch: komaxit; Křídlo_Materiál: Dřevěné; Křídlo_Povrch_Int.: HPL laminát; Křídlo_Povrch_Ext.: HPL laminát; Kování_Klika_Int.: madlo; Kování_Klika_Ext.: madlo; Kování_Zámek: mechanický vložkový; Specifikace: Interiérové dveře jednokřídlé plné posuvné do SDK; Allright_Stavebni_dil_ID: 1464Obj1096313305; Jednotka: Kus; Název_objektu: Dveře - objekt+SmartPart; GlassSurface: 0; HeightWindowSillOutside: 0; HeightWindowSillInside: 0; OffsetOpeningBottom: 0; OffsetOpeningTop: 0; OffsetOpeningLeft: 0; OffsetOpeningRight: 0; DeductionOpeningBottom: 0; DeductionOpeningLeft: 795; DeductionOpeningRight: 50; DeductionOpeningTop: 90
Pset_DoorCommon - Status: NEW; IsExternal: no; ThermalTransmittance: 0 W/K/m2; HandicapAccessible: no; SmokeStop: no; SelfClosing: no; FireExit: no; SecurityRating: bez
Qto_DoorBaseQuantities - Height: 2.06 m; Width: 1.545 m; Area: 3.183 m2; Perimeter: 0 m

# IfcDoor: I.DP07
In: Půdorys 1.NP
Type - PredefinedType: DOOR; ParameterTakesPrecedence: no
OverallHeight: 2.06 m; OverallWidth: 1.545 m
NEMSOK - Kód prvku: DD01.03.1007; Jednotková_cena: 0; V6: 0 m; V7: 0 m; V8: 0 m; V9: 0; Verze programu: 2.2; Označení: I.DP07; Plugin_Bezeichnung: MainObject; Plugin_Objektname: SmartPartCompressed; Uvažované procento prosklení: 100; Verze: 4.0; Podlaží: 1.NP; šířka: 700; výška: 1970; Funkce (venkovní): Ne; Připojení EZS: Ne; Připojení NN: Ne; Připojení EPS: Ne; Připojení MaR: Ne; Připojení ACS: Ne; Typ dveřní zarážky: Bez; Typ samozavírače: bez; Vzduchová neprůzvučnost: 0; Dveře_Světlá-šířka: 0 m; Dveře_Světlá-výška: 0 m; Zárubeň/Rám_Typ: dvoudílná; Zárubeň/Rám_Materiál: Ocelová; Zárubeň/Rám_Povrch: komaxit; Křídlo_Materiál: Dřevěné; Křídlo_Povrch_Int.: HPL laminát; Křídlo_Povrch_Ext.: HPL laminát; Kování_Klika_Int.: madlo; Kování_Klika_Ext.: madlo; Kování_Zámek: WC zámek; Specifikace: Interiérové dveře jednokřídlé plné posuvné do SDK; Allright_Stavebni_dil_ID: 1464Obj1096313311; Jednotka: Kus; Název_objektu: Dveře - objekt+SmartPart; GlassSurface: 0; HeightWindowSillOutside: 0; HeightWindowSillInside: 0; OffsetOpeningBottom: 0; OffsetOpeningTop: 0; OffsetOpeningLeft: 0; OffsetOpeningRight: 0; DeductionOpeningBottom: 0; DeductionOpeningLeft: 795; DeductionOpeningRight: 50; DeductionOpeningTop: 90
Pset_DoorCommon - Status: NEW; IsExternal: no; ThermalTransmittance: 0 W/K/m2; HandicapAccessible: no; SmokeStop: no; SelfClosing: no; FireExit: no; SecurityRating: bez
Qto_DoorBaseQuantities - Height: 2.06 m; Width: 1.545 m; Area: 3.183 m2; Perimeter: 0 m

# IfcDoor: II.D01
In: Půdorys 1.NP
Type - PredefinedType: DOOR; ParameterTakesPrecedence: no
OverallHeight: 2.45 m; OverallWidth: 0.9 m
NEMSOK - Kód prvku: DD01.03.2001; Jednotková_cena: 0; V6: 0 m; V7: 0 m; V8: 0 m; V9: 0; Verze programu: 2.2; Označení: II.D01; Plugin_Bezeichnung: MainObject; Plugin_Objektname: SmartPartCompressed; Uvažované procento prosklení: 100; Verze: 4.0; šířka: 800; výška: 2100; Funkce (venkovní): Ne; Připojení EZS: Ne; Připojení NN: Ne; Připojení EPS: Ne; Připojení MaR: Ne; Připojení ACS: Ne; Typ dveřní zarážky: Plastová nástěnná; Typ samozavírače: Bez; Vzduchová neprůzvučnost: 0; Dveře_Světlá-šířka: 0 m; Dveře_Světlá-výška: 0 m; Zárubeň/Rám_Typ: dvoudílná; Zárubeň/Rám_Materiál: Ocelová; Zárubeň/Rám_Povrch: komaxit; Křídlo_Materiál: Dřevěné; Křídlo_Povrch_Int.: HPL laminát; Křídlo_Povrch_Ext.: HPL laminát; Kování_Klika_Int.: klika; Kování_Klika_Ext.: klika; Kování_Zámek: mechanický vložkový; Specifikace: Interiérové dveře jednokřídlé plné; Allright_Stavebni_dil_ID: 1464Obj0000000323; Jednotka: Kus; Název_objektu: Dveře - objekt+SmartPart; GlassSurface: 0; HeightWindowSillOutside: 0; HeightWindowSillInside: 0; OffsetOpeningBottom: 0; OffsetOpeningTop: 0; OffsetOpeningLeft: 0; OffsetOpeningRight: 0; DeductionOpeningBottom: 300; DeductionOpeningLeft: 50; DeductionOpeningRight: 50; DeductionOpeningTop: 50
Pset_DoorCommon - Status: NEW; IsExternal: no; ThermalTransmittance: 0 W/K/m2; HandicapAccessible: no; SmokeStop: no; SelfClosing: no; FireExit: no; SecurityRating: bez
Qto_DoorBaseQuantities - Height: 2.45 m; Width: 0.9 m; Area: 2.205 m2; Perimeter: 0 m

# IfcDoor: II.D02
In: Půdorys 1.NP
Type - PredefinedType: DOOR; ParameterTakesPrecedence: no
OverallHeight: 2.45 m; OverallWidth: 0.9 m
NEMSOK - Kód prvku: DD01.03.2002; Jednotková_cena: 0; V6: 0 m; V7: 0 m; V8: 0 m; V9: 0; Verze programu: 2.2; Označení: II.D02; Plugin_Bezeichnung: MainObject; Plugin_Objektname: SmartPartCompressed; Uvažované procento prosklení: 100; Verze: 4.0; šířka: 900; výška: 2100; Funkce (venkovní): Ne; Připojení EZS: Ne; Připojení NN: Ne; Připojení EPS: Ne; Připojení MaR: Ne; Připojení ACS: Ne; Typ dveřní zarážky: Plastová nástěnná; Typ samozavírače: Bez; Vzduchová neprůzvučnost: 0; Dveře_Světlá-šířka: 0 m; Dveře_Světlá-výška: 0 m; Zárubeň/Rám_Typ: dvoudílná; Zárubeň/Rám_Materiál: Ocelová; Zárubeň/Rám_Povrch: komaxit; Křídlo_Materiál: Dřevěné; Křídlo_Povrch_Int.: HPL laminát; Křídlo_Povrch_Ext.: HPL laminát; Kování_Klika_Int.: klika; Kování_Klika_Ext.: klika; Kování_Zámek: mechanický vložkový; Specifikace: Interiérové dveře jednokřídlé plné; Allright_Stavebni_dil_ID: 1464Obj1096314358; Jednotka: Kus; Název_objektu: Dveře - objekt+SmartPart; GlassSurface: 0; HeightWindowSillOutside: 0; HeightWindowSillInside: 0; OffsetOpeningBottom: 0; OffsetOpeningTop: 0; OffsetOpeningLeft: 0; OffsetOpeningRight: 0; DeductionOpeningBottom: 300; DeductionOpeningLeft: 50; DeductionOpeningRight: 50; DeductionOpeningTop: 50
Pset_DoorCommon - Status: NEW; IsExternal: no; ThermalTransmittance: 0 W/K/m2; HandicapAccessible: no; SmokeStop: no; SelfClosing: no; FireExit: no; SecurityRating: bez
Qto_DoorBaseQuantities - Height: 2.45 m; Width: 0.9 m; Area: 2.205 m2; Perimeter: 0 m

# IfcDoor: II.D03
In: Půdorys 1.NP
Type - PredefinedType: DOOR; ParameterTakesPrecedence: no
OverallHeight: 2.45 m; OverallWidth: 0.8 m
NEMSOK - Kód prvku: DD01.03.2003; Jednotková_cena: 0; V6: 0 m; V7: 0 m; V8: 0 m; V9: 0; Verze programu: 2.2; Označení: II.D03; Plugin_Bezeichnung: MainObject; Plugin_Objektname: SmartPartCompressed; Uvažované procento prosklení: 100; Verze: 4.0; šířka: 700; výška: 2100; Funkce (venkovní): Ne; Připojení EZS: Ne; Připojení NN: Ne; Připojení EPS: Ne; Připojení MaR: Ne; Připojení ACS: Ne; Typ dveřní zarážky: Plastová nástěnná; Typ samozavírače: Bez; Vzduchová neprůzvučnost: 0; Dveře_Světlá-šířka: 0 m; Dveře_Světlá-výška: 0 m; Zárubeň/Rám_Typ: dvoudílná; Zárubeň/Rám_Materiál: Ocelová; Zárubeň/Rám_Povrch: komaxit; Křídlo_Materiál: Dřevěné; Křídlo_Povrch_Int.: HPL laminát; Křídlo_Povrch_Ext.: HPL laminát; Kování_Klika_Int.: klika; Kování_Klika_Ext.: klika; Kování_Zámek: mechanický vložkový; Specifikace: Interiérové dveře jednokřídlé plné; Allright_Stavebni_dil_ID: 1464Obj1096313031; Jednotka: Kus; Název_objektu: Dveře - objekt+SmartPart; GlassSurface: 0; HeightWindowSillOutside: 0; HeightWindowSillInside: 0; OffsetOpeningBottom: 0; OffsetOpeningTop: 0; OffsetOpeningLeft: 0; OffsetOpeningRight: 0; DeductionOpeningBottom: 300; DeductionOpeningLeft: 50; DeductionOpeningRight: 50; DeductionOpeningTop: 50
Pset_DoorCommon - Status: NEW; IsExternal: no; ThermalTransmittance: 0 W/K/m2; HandicapAccessible: no; SmokeStop: no; SelfClosing: no; FireExit: no; SecurityRating: bez
Qto_DoorBaseQuantities - Height: 2.45 m; Width: 0.8 m; Area: 1.96 m2; Perimeter: 0 m

# IfcDoor: II.D04
In: Půdorys 1.NP
Type - PredefinedType: DOOR; ParameterTakesPrecedence: no
OverallHeight: 2.45 m; OverallWidth: 0.8 m
NEMSOK - Kód prvku: DD01.03.2004; Jednotková_cena: 0; V6: 0 m; V7: 0 m; V8: 0 m; V9: 0; Verze programu: 2.2; Označení: II.D04; Plugin_Bezeichnung: MainObject; Plugin_Objektname: SmartPartCompressed; Uvažované procento prosklení: 100; Verze: 4.0; šířka: 700; výška: 2100; Funkce (venkovní): Ne; Připojení EZS: Ne; Připojení NN: Ne; Připojení EPS: Ne; Připojení MaR: Ne; Připojení ACS: Ne; Typ dveřní zarážky: Plastová nástěnná; Typ samozavírače: Bez; Vzduchová neprůzvučnost: 0; Dveře_Světlá-šířka: 0 m; Dveře_Světlá-výška: 0 m; Zárubeň/Rám_Typ: dvoudílná; Zárubeň/Rám_Materiál: Ocelová; Zárubeň/Rám_Povrch: komaxit; Křídlo_Materiál: Dřevěné; Křídlo_Povrch_Int.: HPL laminát; Křídlo_Povrch_Ext.: HPL laminát; Kování_Klika_Int.: klika; Kování_Klika_Ext.: klika; Kování_Zámek: mechanický vložkový; Specifikace: Interiérové dveře jednokřídlé plné; Allright_Stavebni_dil_ID: 1464Obj0000004743; Jednotka: Kus; Název_objektu: Dveře - objekt+SmartPart; GlassSurface: 0; HeightWindowSillOutside: 0; HeightWindowSillInside: 0; OffsetOpeningBottom: 0; OffsetOpeningTop: 0; OffsetOpeningLeft: 0; OffsetOpeningRight: 0; DeductionOpeningBottom: 300; DeductionOpeningLeft: 50; DeductionOpeningRight: 50; DeductionOpeningTop: 50
Pset_DoorCommon - Status: NEW; IsExternal: no; ThermalTransmittance: 0 W/K/m2; HandicapAccessible: no; SmokeStop: no; SelfClosing: no; FireExit: no; SecurityRating: bez
Qto_DoorBaseQuantities - Height: 2.45 m; Width: 0.8 m; Area: 1.96 m2; Perimeter: 0 m

# IfcDoor: II.D05
In: Půdorys 1.NP
Type - PredefinedType: DOOR; ParameterTakesPrecedence: no
OverallHeight: 2.45 m; OverallWidth: 0.8 m
NEMSOK - Kód prvku: DD01.03.2005; Jednotková_cena: 0; V6: 0 m; V7: 0 m; V8: 0 m; V9: 0; Verze programu: 2.2; Označení: II.D05; Plugin_Bezeichnung: MainObject; Plugin_Objektname: SmartPartCompressed; Uvažované procento prosklení: 100; Verze: 4.0; šířka: 700; výška: 2100; Funkce (venkovní): Ne; Připojení EZS: Ne; Připojení NN: Ne; Připojení EPS: Ne; Připojení MaR: Ne; Připojení ACS: Ne; Typ dveřní zarážky: Plastová nástěnná; Typ samozavírače: Hřebenový s kluznou lištou; Vzduchová neprůzvučnost: 0; Dveře_Světlá-šířka: 0 m; Dveře_Světlá-výška: 0 m; Zárubeň/Rám_Typ: dvoudílná; Zárubeň/Rám_Materiál: Ocelová; Zárubeň/Rám_Povrch: komaxit; Křídlo_Materiál: Dřevěné; Křídlo_Povrch_Int.: HPL laminát; Křídlo_Povrch_Ext.: HPL laminát; Kování_Klika_Int.: klika; Kování_Klika_Ext.: klika; Kování_Zámek: WC zámek; Specifikace: Interiérové dveře jednokřídlé plné; Allright_Stavebni_dil_ID: 1464Obj1096314448; Jednotka: Kus; Název_objektu: Dveře - objekt+SmartPart; GlassSurface: 0; HeightWindowSillOutside: 0; HeightWindowSillInside: 0; OffsetOpeningBottom: 0; OffsetOpeningTop: 0; OffsetOpeningLeft: 0; OffsetOpeningRight: 0; DeductionOpeningBottom: 300; DeductionOpeningLeft: 50; DeductionOpeningRight: 50; DeductionOpeningTop: 50
Pset_DoorCommon - Status: NEW; IsExternal: no; ThermalTransmittance: 0 W/K/m2; HandicapAccessible: no; SmokeStop: no; SelfClosing: no; FireExit: no; SecurityRating: bez
Qto_DoorBaseQuantities - Height: 2.45 m; Width: 0.8 m; Area: 1.96 m2; Perimeter: 0 m

# IfcDoor: II.D06
In: Půdorys 1.NP
Type - PredefinedType: DOOR; ParameterTakesPrecedence: no
OverallHeight: 2.45 m; OverallWidth: 0.8 m
NEMSOK - Kód prvku: DD01.03.2006; Jednotková_cena: 0; V6: 0 m; V7: 0 m; V8: 0 m; V9: 0; Verze programu: 2.2; Označení: II.D06; Plugin_Bezeichnung: MainObject; Plugin_Objektname: SmartPartCompressed; Uvažované procento prosklení: 100; Verze: 4.0; šířka: 700; výška: 2100; Funkce (venkovní): Ne; Připojení EZS: Ne; Připojení NN: Ne; Připojení EPS: Ne; Připojení MaR: Ne; Připojení ACS: Ne; Typ dveřní zarážky: Plastová nástěnná; Typ samozavírače: Bez; Vzduchová neprůzvučnost: 0; Dveře_Světlá-šířka: 0 m; Dveře_Světlá-výška: 0 m; Zárubeň/Rám_Typ: dvoudílná; Zárubeň/Rám_Materiál: Ocelová; Zárubeň/Rám_Povrch: komaxit; Křídlo_Materiál: Dřevěné; Křídlo_Povrch_Int.: HPL laminát; Křídlo_Povrch_Ext.: HPL laminát; Kování_Klika_Int.: klika; Kování_Klika_Ext.: klika; Kování_Zámek: WC zámek; Specifikace: Interiérové dveře jednokřídlé plné; Allright_Stavebni_dil_ID: 1464Obj1096313217; Jednotka: Kus; Název_objektu: Dveře - objekt+SmartPart; GlassSurface: 0; HeightWindowSillOutside: 0; HeightWindowSillInside: 0; OffsetOpeningBottom: 0; OffsetOpeningTop: 0; OffsetOpeningLeft: 0; OffsetOpeningRight: 0; DeductionOpeningBottom: 300; DeductionOpeningLeft: 50; DeductionOpeningRight: 50; DeductionOpeningTop: 50
Pset_DoorCommon - Status: NEW; IsExternal: no; ThermalTransmittance: 0 W/K/m2; HandicapAccessible: no; SmokeStop: no; SelfClosing: no; FireExit: no; SecurityRating: bez
Qto_DoorBaseQuantities - Height: 2.45 m; Width: 0.8 m; Area: 1.96 m2; Perimeter: 0 m

# IfcDoor: II.D07
In: Půdorys 1.NP
Type - PredefinedType: DOOR; ParameterTakesPrecedence: no
OverallHeight: 2.45 m; OverallWidth: 1 m
NEMSOK - Kód prvku: DD01.03.2007; Jednotková_cena: 0; V6: 0 m; V7: 0 m; V8: 0 m; V9: 0; Verze programu: 2.2; Označení: II.D07; Plugin_Bezeichnung: MainObject; Plugin_Objektname: SmartPartCompressed; Uvažované procento prosklení: 100; Verze: 4.0; šířka: 900; výška: 2100; Funkce (venkovní): Ne; Připojení EZS: Ne; Připojení NN: Ne; Připojení EPS: Ne; Připojení MaR: Ne; Připojení ACS: Ne; Typ dveřní zarážky: Bez; Typ samozavírače: Hřebenový s kluznou lištou; Vzduchová neprůzvučnost: 0; Dveře_Světlá-šířka: 0 m; Dveře_Světlá-výška: 0 m; Zárubeň/Rám_Typ: dvoudílná; Zárubeň/Rám_Materiál: Ocelová; Zárubeň/Rám_Povrch: komaxit; Křídlo_Materiál: Dřevěné; Křídlo_Povrch_Int.: HPL laminát; Křídlo_Povrch_Ext.: HPL laminát; Kování_Klika_Int.: klika; Kování_Klika_Ext.: koule; Kování_Zámek: mechanický vložkový; Specifikace: Interiérové dveře jednokřídlé plné; Allright_Stavebni_dil_ID: 1464Obj0000001098; Jednotka: Kus; Název_objektu: Dveře - objekt+SmartPart; GlassSurface: 0; HeightWindowSillOutside: 0; HeightWindowSillInside: 0; OffsetOpeningBottom: 0; OffsetOpeningTop: 0; OffsetOpeningLeft: 0; OffsetOpeningRight: 0; DeductionOpeningBottom: 300; DeductionOpeningLeft: 50; DeductionOpeningRight: 50; DeductionOpeningTop: 50
Pset_DoorCommon - Status: NEW; IsExternal: no; ThermalTransmittance: 0 W/K/m2; HandicapAccessible: no; SmokeStop: no; SelfClosing: no; FireExit: no; SecurityRating: bez
Qto_DoorBaseQuantities - Height: 2.45 m; Width: 1 m; Area: 2.45 m2; Perimeter: 0 m

# IfcDoor: II.D08
In: Půdorys 1.NP
Type - PredefinedType: DOOR; ParameterTakesPrecedence: no
OverallHeight: 2.25 m; OverallWidth: 0.9 m
NEMSOK - Kód prvku: DD01.03.2008; Jednotková_cena: 0; V6: 0 m; V7: 0 m; V8: 0 m; V9: 0; Verze programu: 2.2; Označení: II.D08; Plugin_Bezeichnung: MainObject; Plugin_Objektname: SmartPartCompressed; Uvažované procento prosklení: 100; Verze: 4.0; šířka: 800; výška: 2100; Funkce (venkovní): Ne; Připojení EZS: Ne; Připojení NN: Ne; Připojení EPS: Ne; Připojení MaR: Ne; Připojení ACS: Ne; Typ dveřní zarážky: Bez; Typ samozavírače: Hřebenový s kluznou lištou; Vzduchová neprůzvučnost: 0; Dveře_Světlá-šířka: 0 m; Dveře_Světlá-výška: 0 m; Zárubeň/Rám_Typ: dvoudílná; Zárubeň/Rám_Materiál: Ocelová; Zárubeň/Rám_Povrch: komaxit; Křídlo_Materiál: Dřevěné; Křídlo_Povrch_Int.: HPL laminát; Křídlo_Povrch_Ext.: HPL laminát; Kování_Klika_Int.: klika; Kování_Klika_Ext.: koule; Kování_Zámek: mechanický vložkový; Specifikace: Interiérové dveře jednokřídlé plné; Allright_Stavebni_dil_ID: 1464Obj1096314512; Jednotka: Kus; Název_objektu: Dveře - objekt+SmartPart; GlassSurface: 0.09; HeightWindowSillOutside: 0; HeightWindowSillInside: 0; OffsetOpeningBottom: 0; OffsetOpeningTop: 0; OffsetOpeningLeft: 0; OffsetOpeningRight: 0; DeductionOpeningBottom: 100; DeductionOpeningLeft: 50; DeductionOpeningRight: 50; DeductionOpeningTop: 50
Pset_DoorCommon - Status: NEW; IsExternal: no; ThermalTransmittance: 0 W/K/m2; HandicapAccessible: no; SmokeStop: no; SelfClosing: no; FireExit: no; SecurityRating: bez
Qto_DoorBaseQuantities - Height: 2.25 m; Width: 0.9 m; Area: 2.025 m2; Perimeter: 0 m

# IfcDoor: II.D09
In: Půdorys 1.NP
Type - PredefinedType: DOOR; ParameterTakesPrecedence: no
OverallHeight: 2.25 m; OverallWidth: 0.9 m
NEMSOK - Kód prvku: DD01.03.2009; Jednotková_cena: 0; V6: 0 m; V7: 0 m; V8: 0 m; V9: 0; Verze programu: 2.2; Označení: II.D09; Plugin_Bezeichnung: MainObject; Plugin_Objektname: SmartPartCompressed; Uvažované procento prosklení: 100; Verze: 4.0; šířka: 800; výška: 2100; Funkce (venkovní): Ne; Připojení EZS: Ne; Připojení NN: Ne; Připojení EPS: Ne; Připojení MaR: Ne; Připojení ACS: Ne; Typ dveřní zarážky: Bez; Typ samozavírače: Hřebenový s kluznou lištou; Vzduchová neprůzvučnost: 0; Dveře_Světlá-šířka: 0 m; Dveře_Světlá-výška: 0 m; Zárubeň/Rám_Typ: dvoudílná; Zárubeň/Rám_Materiál: Ocelová; Zárubeň/Rám_Povrch: komaxit; Křídlo_Materiál: Dřevěné; Křídlo_Povrch_Int.: HPL laminát; Křídlo_Povrch_Ext.: HPL laminát; Kování_Klika_Int.: klika; Kování_Klika_Ext.: koule; Kování_Zámek: mechanický vložkový; Specifikace: Interiérové dveře jednokřídlé plné; Allright_Stavebni_dil_ID: 1464Obj1096314656; Jednotka: Kus; Název_objektu: Dveře - objekt+SmartPart; GlassSurface: 0.09; HeightWindowSillOutside: 0; HeightWindowSillInside: 0; OffsetOpeningBottom: 0; OffsetOpeningTop: 0; OffsetOpeningLeft: 0; OffsetOpeningRight: 0; DeductionOpeningBottom: 100; DeductionOpeningLeft: 50; DeductionOpeningRight: 50; DeductionOpeningTop: 50
Pset_DoorCommon - Status: NEW; IsExternal: no; ThermalTransmittance: 0 W/K/m2; HandicapAccessible: no; SmokeStop: no; SelfClosing: no; FireExit: no; SecurityRating: bez
Qto_DoorBaseQuantities - Height: 2.25 m; Width: 0.9 m; Area: 2.025 m2; Perimeter: 0 m

# IfcDoor: II.D10
In: Půdorys 1.NP
Type - PredefinedType: DOOR; ParameterTakesPrecedence: no
OverallHeight: 2.25 m; OverallWidth: 0.9 m
NEMSOK - Kód prvku: DD01.03.2010; Jednotková_cena: 0; V6: 0 m; V7: 0 m; V8: 0 m; V9: 0; Verze programu: 2.2; Označení: II.D10; Plugin_Bezeichnung: MainObject; Plugin_Objektname: SmartPartCompressed; Uvažované procento prosklení: 100; Verze: 4.0; šířka: 800; výška: 2100; Funkce (venkovní): Ne; Připojení EZS: Ne; Připojení NN: Ne; Připojení EPS: Ne; Připojení MaR: Ne; Připojení ACS: Ne; Typ dveřní zarážky: Plastová nástěnná; Typ samozavírače: Hřebenový s kluznou lištou; Vzduchová neprůzvučnost: 0; Dveře_Světlá-šířka: 0 m; Dveře_Světlá-výška: 0 m; Zárubeň/Rám_Typ: dvoudílná; Zárubeň/Rám_Materiál: Ocelová; Zárubeň/Rám_Povrch: komaxit; Křídlo_Materiál: Dřevěné; Křídlo_Povrch_Int.: HPL laminát; Křídlo_Povrch_Ext.: HPL laminát; Kování_Klika_Int.: klika; Kování_Klika_Ext.: klika; Kování_Zámek: WC zámek; Specifikace: Interiérové dveře jednokřídlé plné; Allright_Stavebni_dil_ID: 1464Obj1096314556; Jednotka: Kus; Název_objektu: Dveře - objekt+SmartPart; GlassSurface: 0.09; HeightWindowSillOutside: 0; HeightWindowSillInside: 0; OffsetOpeningBottom: 0; OffsetOpeningTop: 0; OffsetOpeningLeft: 0; OffsetOpeningRight: 0; DeductionOpeningBottom: 100; DeductionOpeningLeft: 50; DeductionOpeningRight: 50; DeductionOpeningTop: 50
Pset_DoorCommon - Status: NEW; IsExternal: no; ThermalTransmittance: 0 W/K/m2; HandicapAccessible: no; SmokeStop: no; SelfClosing: no; FireExit: no; SecurityRating: bez
Qto_DoorBaseQuantities - Height: 2.25 m; Width: 0.9 m; Area: 2.025 m2; Perimeter: 0 m

# IfcDoor: II.D11
In: Půdorys 1.NP
Type - PredefinedType: DOOR; ParameterTakesPrecedence: no
OverallHeight: 2.25 m; OverallWidth: 0.9 m
NEMSOK - Kód prvku: DD01.03.2011; Jednotková_cena: 0; V6: 0 m; V7: 0 m; V8: 0 m; V9: 0; Verze programu: 2.2; Označení: II.D11; Plugin_Bezeichnung: MainObject; Plugin_Objektname: SmartPartCompressed; Uvažované procento prosklení: 100; Verze: 4.0; šířka: 800; výška: 2100; Funkce (venkovní): Ne; Připojení EZS: Ne; Připojení NN: Ne; Připojení EPS: Ne; Připojení MaR: Ne; Připojení ACS: Ne; Typ dveřní zarážky: Plastová nástěnná; Typ samozavírače: Hřebenový s kluznou lištou; Vzduchová neprůzvučnost: 0; Dveře_Světlá-šířka: 0 m; Dveře_Světlá-výška: 0 m; Zárubeň/Rám_Typ: dvoudílná; Zárubeň/Rám_Materiál: Ocelová; Zárubeň/Rám_Povrch: komaxit; Křídlo_Materiál: Dřevěné; Křídlo_Povrch_Int.: HPL laminát; Křídlo_Povrch_Ext.: HPL laminát; Kování_Klika_Int.: klika; Kování_Klika_Ext.: klika; Kování_Zámek: mechanický vložkový; Specifikace: Interiérové dveře jednokřídlé plné; Allright_Stavebni_dil_ID: 1464Obj1096314598; Jednotka: Kus; Název_objektu: Dveře - objekt+SmartPart; GlassSurface: 0.09; HeightWindowSillOutside: 0; HeightWindowSillInside: 0; OffsetOpeningBottom: 0; OffsetOpeningTop: 0; OffsetOpeningLeft: 0; OffsetOpeningRight: 0; DeductionOpeningBottom: 100; DeductionOpeningLeft: 50; DeductionOpeningRight: 50; DeductionOpeningTop: 50
Pset_DoorCommon - Status: NEW; IsExternal: no; ThermalTransmittance: 0 W/K/m2; HandicapAccessible: no; SmokeStop: no; SelfClosing: no; FireExit: no; SecurityRating: bez
Qto_DoorBaseQuantities - Height: 2.25 m; Width: 0.9 m; Area: 2.025 m2; Perimeter: 0 m

# IfcDoor: II.D12
In: Půdorys 1.NP
Type - PredefinedType: DOOR; ParameterTakesPrecedence: no
OverallHeight: 2.25 m; OverallWidth: 0.8 m
NEMSOK - Kód prvku: DD01.03.2012; Jednotková_cena: 0; V6: 0 m; V7: 0 m; V8: 0 m; V9: 0; Verze programu: 2.2; Označení: II.D12; Plugin_Bezeichnung: MainObject; Plugin_Objektname: SmartPartCompressed; Uvažované procento prosklení: 100; Verze: 4.0; šířka: 700; výška: 2100; Funkce (venkovní): Ne; Připojení EZS: Ne; Připojení NN: Ne; Připojení EPS: Ne; Připojení MaR: Ne; Připojení ACS: Ne; Typ dveřní zarážky: Plastová nástěnná; Typ samozavírače: Bez; Vzduchová neprůzvučnost: 0; Dveře_Světlá-šířka: 0 m; Dveře_Světlá-výška: 0 m; Zárubeň/Rám_Typ: dvoudílná; Zárubeň/Rám_Materiál: Ocelová; Zárubeň/Rám_Povrch: komaxit; Křídlo_Materiál: Dřevěné; Křídlo_Povrch_Int.: HPL laminát; Křídlo_Povrch_Ext.: HPL laminát; Kování_Klika_Int.: klika; Kování_Klika_Ext.: klika; Kování_Zámek: WC zámek; Specifikace: Interiérové dveře jednokřídlé plné; Allright_Stavebni_dil_ID: 1464Obj1096314625; Jednotka: Kus; Název_objektu: Dveře - objekt+SmartPart; GlassSurface: 0.08; HeightWindowSillOutside: 0; HeightWindowSillInside: 0; OffsetOpeningBottom: 0; OffsetOpeningTop: 0; OffsetOpeningLeft: 0; OffsetOpeningRight: 0; DeductionOpeningBottom: 100; DeductionOpeningLeft: 50; DeductionOpeningRight: 50; DeductionOpeningTop: 50
Pset_DoorCommon - Status: NEW; IsExternal: no; ThermalTransmittance: 0 W/K/m2; HandicapAccessible: no; SmokeStop: no; SelfClosing: no; FireExit: no; SecurityRating: bez
Qto_DoorBaseQuantities - Height: 2.25 m; Width: 0.8 m; Area: 1.8 m2; Perimeter: 0 m

# IfcDoor: II.D13
In: Půdorys 1.NP
Type - PredefinedType: DOOR; ParameterTakesPrecedence: no
OverallHeight: 2.25 m; OverallWidth: 0.9 m
NEMSOK - Kód prvku: DD01.03.2013; Jednotková_cena: 0; V6: 0 m; V7: 0 m; V8: 0 m; V9: 0; Verze programu: 2.2; Označení: II.D13; Plugin_Bezeichnung: MainObject; Plugin_Objektname: SmartPartCompressed; Uvažované procento prosklení: 100; Verze: 4.0; šířka: 800; výška: 2100; Funkce (venkovní): Ne; Připojení EZS: Ne; Připojení NN: Ne; Připojení EPS: Ne; Připojení MaR: Ne; Připojení ACS: Ne; Typ dveřní zarážky: Plastová nástěnná; Typ samozavírače: Hřebenový s kluznou lištou; Vzduchová neprůzvučnost: 0; Dveře_Světlá-šířka: 0 m; Dveře_Světlá-výška: 0 m; Zárubeň/Rám_Typ: dvoudílná; Zárubeň/Rám_Materiál: Ocelová; Zárubeň/Rám_Povrch: komaxit; Křídlo_Materiál: Dřevěné; Křídlo_Povrch_Int.: HPL laminát; Křídlo_Povrch_Ext.: HPL laminát; Kování_Klika_Int.: klika; Kování_Klika_Ext.: koule; Kování_Zámek: mechanický vložkový; Specifikace: Interiérové dveře jednokřídlé plné; Allright_Stavebni_dil_ID: 1464Obj1096313180; Jednotka: Kus; Název_objektu: Dveře - objekt+SmartPart; GlassSurface: 0.09; HeightWindowSillOutside: 0; HeightWindowSillInside: 0; OffsetOpeningBottom: 0; OffsetOpeningTop: 0; OffsetOpeningLeft: 0; OffsetOpeningRight: 0; DeductionOpeningBottom: 100; DeductionOpeningLeft: 50; DeductionOpeningRight: 50; DeductionOpeningTop: 50
Pset_DoorCommon - Status: NEW; IsExternal: no; ThermalTransmittance: 0 W/K/m2; HandicapAccessible: no; SmokeStop: no; SelfClosing: no; FireExit: no; SecurityRating: bez
Qto_DoorBaseQuantities - Height: 2.25 m; Width: 0.9 m; Area: 2.025 m2; Perimeter: 0 m

# IfcDoor: II.DF01
In: Půdorys 1.NP
Type - PredefinedType: DOOR; ParameterTakesPrecedence: no
OverallHeight: 3.2 m; OverallWidth: 3.5 m
NEMSOK - Kód prvku: DD03.03.2101; Jednotková_cena: 0; V6: 0 m; V7: 0 m; V8: 0 m; V9: 0; Verze programu: 2.2; Označení: II.DF01; Plugin_Bezeichnung: MainObject; Plugin_Objektname: SmartPartCompressed; Uvažované procento prosklení: 0; Verze: 4.0; šířka: 1600; výška: 2100; Funkce (venkovní): Ano; Připojení EZS: Ano; Připojení NN: Ne; Připojení EPS: Ne; Připojení MaR: Ne; Připojení ACS: Ne; Typ dveřní zarážky: Bez; Typ samozavírače: Hřebenový s kluznou lištou; Vzduchová neprůzvučnost: 0; Dveře_Světlá-šířka: 0.9 m; Dveře_Světlá-výška: 0 m; Zárubeň/Rám_Typ: rámová; Zárubeň/Rám_Materiál: Hliníková; Zárubeň/Rám_Povrch: elox; Křídlo_Materiál: Hliníkové; Kování_Klika_Int.: klika; Kování_Klika_Ext.: paniková klika; Kování_Zámek: mechanický vložkový; Specifikace: Vchodové dveře dvoukřídlé prosklené s boční prosklenou pevnou částí a nasvětlíkem; Allright_Stavebni_dil_ID: 1464Obj1096219498; Jednotka: Kus; Název_objektu: Dveře - objekt+SmartPart; GlassSurface: 7.81305; HeightWindowSillOutside: 0; HeightWindowSillInside: 0; OffsetOpeningBottom: 0; OffsetOpeningTop: 0; OffsetOpeningLeft: 0; OffsetOpeningRight: 0; DeductionOpeningBottom: 300; DeductionOpeningLeft: 100; DeductionOpeningRight: 1800; DeductionOpeningTop: 800
Pset_DoorCommon - Status: NEW; IsExternal: yes; ThermalTransmittance: 0.9 W/K/m2; HandicapAccessible: no; SmokeStop: no; SelfClosing: no; FireExit: no; SecurityRating: bez
Qto_DoorBaseQuantities - Height: 3.2 m; Width: 3.5 m; Area: 11.2 m2; Perimeter: 0 m

# IfcDoor: II.DF02
In: Půdorys 1.NP
Type - PredefinedType: DOOR; ParameterTakesPrecedence: no
OverallHeight: 2.85 m; OverallWidth: 1.8 m
NEMSOK - Kód prvku: DD03.03.2102; Jednotková_cena: 0; V6: 0 m; V7: 0 m; V8: 0 m; V9: 0; Verze programu: 2.2; Označení: II.DF02; Plugin_Bezeichnung: MainObject; Plugin_Objektname: SmartPartCompressed; Uvažované procento prosklení: 0; Verze: 4.0; šířka: 1600; výška: 2100; Funkce (venkovní): Ano; Připojení EZS: Ne; Připojení NN: Ne; Připojení EPS: Ne; Připojení MaR: Ne; Připojení ACS: Ano; Typ dveřní zarážky: Bez; Typ samozavírače: Hřebenový s kluznou lištou; Vzduchová neprůzvučnost: 0; Dveře_Světlá-šířka: 0.9 m; Dveře_Světlá-výška: 0 m; Zárubeň/Rám_Typ: rámová; Zárubeň/Rám_Materiál: Hliníková; Zárubeň/Rám_Povrch: elox; Křídlo_Materiál: Hliníkové; Kování_Klika_Int.: klika; Kování_Klika_Ext.: koule; Kování_Zámek: mechanický vložkový; Specifikace: Vchodové dveře dvoukřídlé prosklené s proskleným nasvětlíkem; Allright_Stavebni_dil_ID: 1464Obj1096325918; Jednotka: Kus; Název_objektu: Dveře - objekt+SmartPart; GlassSurface: 3.25305; HeightWindowSillOutside: 0; HeightWindowSillInside: 0; OffsetOpeningBottom: 0; OffsetOpeningTop: 0; OffsetOpeningLeft: 0; OffsetOpeningRight: 0; DeductionOpeningBottom: 100; DeductionOpeningLeft: 100; DeductionOpeningRight: 100; DeductionOpeningTop: 650
Pset_DoorCommon - Status: NEW; IsExternal: yes; ThermalTransmittance: 0.9 W/K/m2; HandicapAccessible: no; SmokeStop: no; SelfClosing: no; FireExit: no; SecurityRating: bez
Qto_DoorBaseQuantities - Height: 2.85 m; Width: 1.8 m; Area: 5.13 m2; Perimeter: 0 m

# IfcDoor: II.DH01
In: Půdorys 1.NP
Type - PredefinedType: DOOR; ParameterTakesPrecedence: no
OverallHeight: 2.24 m; OverallWidth: 1.88 m
NEMSOK - Kód prvku: DD03.03.2001; Jednotková_cena: 0; V6: 0 m; V7: 0 m; V8: 0 m; V9: 0; Verze programu: 2.2; Označení: II.DH01; Plugin_Bezeichnung: MainObject; Plugin_Objektname: SmartPartCompressed; Uvažované procento prosklení: 100; Verze: 4.0; šířka: 1800; výška: 2100; Funkce (venkovní): Ne; Připojení EZS: Ano; Připojení NN: Ano; Připojení EPS: Ne; Připojení MaR: Ne; Připojení ACS: Ne; Typ dveřní zarážky: Bez; Typ samozavírače: Bez; Vzduchová neprůzvučnost: 0; Dveře_Světlá-šířka: 0 m; Dveře_Světlá-výška: 0 m; Zárubeň/Rám_Typ: rámová; Zárubeň/Rám_Materiál: Hliníková; Zárubeň/Rám_Povrch: elox; Křídlo_Materiál: Hliníkové; Kování_Klika_Int.: radar; Kování_Klika_Ext.: radar; Kování_Zámek: podlahový zámek; Specifikace: Interiérové dveře automatické posuvné dvoupanelové prosklené; Allright_Stavebni_dil_ID: 1464Obj1096312927; Jednotka: Kus; Název_objektu: Dveře - objekt+SmartPart; GlassSurface: 3.10555; HeightWindowSillOutside: 0; HeightWindowSillInside: 0; OffsetOpeningBottom: 0; OffsetOpeningTop: 0; OffsetOpeningLeft: 0; OffsetOpeningRight: 0; DeductionOpeningBottom: 100; DeductionOpeningLeft: 20; DeductionOpeningRight: 20; DeductionOpeningTop: 20
Pset_DoorCommon - Status: NEW; IsExternal: no; FireRating: EW 30DP1-C; ThermalTransmittance: 0 W/K/m2; HandicapAccessible: no; SmokeStop: no; SelfClosing: no; FireExit: no; SecurityRating: bez
Qto_DoorBaseQuantities - Height: 2.22 m; Width: 1.84 m; Area: 4.085 m2; Perimeter: 0 m

# IfcDoor: II.DH02
In: Půdorys 1.NP
Type - PredefinedType: DOOR; ParameterTakesPrecedence: no
OverallHeight: 3 m; OverallWidth: 1.75 m
NEMSOK - Kód prvku: DD03.03.2002; Jednotková_cena: 0; V6: 0 m; V7: 0 m; V8: 0 m; V9: 0; Verze programu: 2.2; Označení: II.DH02; Plugin_Bezeichnung: MainObject; Plugin_Objektname: SmartPartCompressed; Uvažované procento prosklení: 100; Verze: 4.0; Podlaží: 1.NP; šířka: 1600; výška: 2100; Funkce (venkovní): Ne; Připojení EZS: Ne; Připojení NN: Ano; Připojení EPS: Ano; Připojení MaR: Ne; Připojení ACS: Ne; Typ dveřní zarážky: Bez; Typ samozavírače: Hřebenový s kluznou lištou + požární konzole; Vzduchová neprůzvučnost: 0; Dveře_Světlá-šířka: 0.9 m; Dveře_Světlá-výška: 0 m; Zárubeň/Rám_Typ: rámová; Zárubeň/Rám_Materiál: Hliníková; Zárubeň/Rám_Povrch: elox; Křídlo_Materiál: Hliníkové; Kování_Klika_Int.: klika; Kování_Klika_Ext.: klika; Kování_Zámek: mechanický vložkový; Specifikace: Interiérové dveře dvoukřídlé prosklené s nasvětlíkem; Allright_Stavebni_dil_ID: 1464Obj1096207919; Jednotka: Kus; Název_objektu: Dveře - objekt+SmartPart; GlassSurface: 3.73305; HeightWindowSillOutside: 0; HeightWindowSillInside: 0; OffsetOpeningBottom: 0; OffsetOpeningTop: 0; OffsetOpeningLeft: 0; OffsetOpeningRight: 0; DeductionOpeningBottom: 0; DeductionOpeningLeft: 75; DeductionOpeningRight: 75; DeductionOpeningTop: 900
Pset_DoorCommon - Status: NEW; IsExternal: no; FireRating: EI 30DP1-Sm-C; ThermalTransmittance: 0 W/K/m2; HandicapAccessible: no; SmokeStop: no; SelfClosing: no; FireExit: no; SecurityRating: bez
Qto_DoorBaseQuantities - Height: 3 m; Width: 1.75 m; Area: 5.25 m2; Perimeter: 0 m

# IfcDoor: II.DP01
In: Půdorys 1.NP
Type - PredefinedType: DOOR; ParameterTakesPrecedence: no
OverallHeight: 2.19 m; OverallWidth: 1.945 m
NEMSOK - Kód prvku: DD01.03.2101; Jednotková_cena: 0; V6: 0 m; V7: 0 m; V8: 0 m; V9: 0; Verze programu: 2.2; Označení: II.DP01; Plugin_Bezeichnung: MainObject; Plugin_Objektname: SmartPartCompressed; Uvažované procento prosklení: 100; Verze: 4.0; šířka: 900; výška: 2100; Funkce (venkovní): Ne; Připojení EZS: Ne; Připojení NN: Ne; Připojení EPS: Ne; Připojení MaR: Ne; Připojení ACS: Ne; Typ dveřní zarážky: Bez; Typ samozavírače: Bez; Vzduchová neprůzvučnost: 0; Dveře_Světlá-šířka: 0 m; Dveře_Světlá-výška: 0 m; Zárubeň/Rám_Typ: dvoudílná; Zárubeň/Rám_Materiál: Ocelová; Zárubeň/Rám_Povrch: komaxit; Křídlo_Materiál: Dřevěné; Křídlo_Povrch_Int.: HPL laminát; Křídlo_Povrch_Ext.: HPL laminát; Kování_Klika_Int.: madlo; Kování_Klika_Ext.: madlo; Kování_Zámek: mechanický vložkový; Specifikace: Interiérové dveře jednokřídlé plné posuvné do SDK; Allright_Stavebni_dil_ID: 1464Obj1096313454; Jednotka: Kus; Název_objektu: Dveře - objekt+SmartPart; GlassSurface: 0; HeightWindowSillOutside: 0; HeightWindowSillInside: 0; OffsetOpeningBottom: 0; OffsetOpeningTop: 0; OffsetOpeningLeft: 0; OffsetOpeningRight: 0; DeductionOpeningBottom: 0; DeductionOpeningLeft: 995; DeductionOpeningRight: 50; DeductionOpeningTop: 90
Pset_DoorCommon - Status: NEW; IsExternal: no; ThermalTransmittance: 0 W/K/m2; HandicapAccessible: no; SmokeStop: no; SelfClosing: no; FireExit: no; SecurityRating: bez
Qto_DoorBaseQuantities - Height: 2.19 m; Width: 1.945 m; Area: 4.26 m2; Perimeter: 0 m

# IfcDoor: II.DP02
In: Půdorys 1.NP
Type - PredefinedType: DOOR; ParameterTakesPrecedence: no
OverallHeight: 2.19 m; OverallWidth: 1.545 m
NEMSOK - Kód prvku: DD01.03.2102; Jednotková_cena: 0; V6: 0 m; V7: 0 m; V8: 0 m; V9: 0; Verze programu: 2.2; Označení: II.DP02; Plugin_Bezeichnung: MainObject; Plugin_Objektname: SmartPartCompressed; Uvažované procento prosklení: 100; Verze: 4.0; šířka: 700; výška: 2100; Funkce (venkovní): Ne; Připojení EZS: Ne; Připojení NN: Ne; Připojení EPS: Ne; Připojení MaR: Ne; Připojení ACS: Ne; Typ dveřní zarážky: Bez; Typ samozavírače: Bez; Vzduchová neprůzvučnost: 0; Dveře_Světlá-šířka: 0 m; Dveře_Světlá-výška: 0 m; Zárubeň/Rám_Typ: dvoudílná; Zárubeň/Rám_Materiál: Ocelová; Zárubeň/Rám_Povrch: komaxit; Křídlo_Materiál: Dřevěné; Křídlo_Povrch_Int.: HPL laminát; Křídlo_Povrch_Ext.: HPL laminát; Kování_Klika_Int.: madlo; Kování_Klika_Ext.: madlo; Kování_Zámek: mechanický vložkový; Specifikace: Interiérové dveře jednokřídlé plné posuvné do SDK; Allright_Stavebni_dil_ID: 1464Obj1096313029; Jednotka: Kus; Název_objektu: Dveře - objekt+SmartPart; GlassSurface: 0; HeightWindowSillOutside: 0; HeightWindowSillInside: 0; OffsetOpeningBottom: 0; OffsetOpeningTop: 0; OffsetOpeningLeft: 0; OffsetOpeningRight: 0; DeductionOpeningBottom: 0; DeductionOpeningLeft: 795; DeductionOpeningRight: 50; DeductionOpeningTop: 90
Pset_DoorCommon - Status: NEW; IsExternal: no; ThermalTransmittance: 0 W/K/m2; HandicapAccessible: no; SmokeStop: no; SelfClosing: no; FireExit: no; SecurityRating: bez
Qto_DoorBaseQuantities - Height: 2.19 m; Width: 1.545 m; Area: 3.384 m2; Perimeter: 0 m

# IfcDoor: SMT
In: Půdorys 1.PP
Type - PredefinedType: DOOR; ParameterTakesPrecedence: no
OverallHeight: 2 m; OverallWidth: 0.76 m
NEMSOK - Kód prvku: SN16.02.0003; Jednotková_cena: 0; V6: 0 m; V7: 0 m; V8: 0 m; V9: 0; Verze programu: 2.2; Označení: SMT; Plugin_Bezeichnung: MainObject; Plugin_Objektname: SmartPartCompressed; Uvažované procento prosklení: 0; Verze: 4.0; Podlaží: 1.PP; šířka: 700; výška: 1970; Funkce (venkovní): Ne; Připojení EZS: Ne; Připojení NN: Ne; Připojení EPS: Ne; Připojení MaR: Ne; Připojení ACS: Ne; Typ dveřní zarážky: Bez; Typ samozavírače: Bez; Vzduchová neprůzvučnost: 0; Dveře_Světlá-šířka: 0 m; Dveře_Světlá-výška: 0 m; Zárubeň/Rám_Materiál: Ocelová; Zárubeň/Rám_Povrch: EH; Kování_Klika_Int.: klika; Kování_Klika_Ext.: klika; Specifikace: Interiérové dveře jednokřídlé plné; Allright_Stavebni_dil_ID: 1364Obj0000010603; Jednotka: Kus; Název_objektu: Dveře - objekt+SmartPart; GlassSurface: 0; HeightWindowSillOutside: 0; HeightWindowSillInside: 0; OffsetOpeningBottom: 0; OffsetOpeningTop: 0; OffsetOpeningLeft: 0; OffsetOpeningRight: 0; DeductionOpeningBottom: 0; DeductionOpeningLeft: 30; DeductionOpeningRight: 30; DeductionOpeningTop: 30
Pset_DoorCommon - Status: NEW; IsExternal: no; ThermalTransmittance: 0 W/K/m2; HandicapAccessible: no; SmokeStop: no; SelfClosing: no; FireExit: no; SecurityRating: SA
Qto_DoorBaseQuantities - Height: 2 m; Width: 0.76 m; Area: 1.52 m2; Perimeter: 0 m

# IfcElementAssembly (27)
NEMSOK - Jednotka: Kus; Název_objektu: Skupina elementů
Name | In | Označení | Allright_Stavebni_dil_ID
Šatní skříňka s předlavičkou | Půdorys 1.NP | Šatní skříňka s předlavičkou | 1465SEl0000024641
Šatní skříňka s předlavičkou | Půdorys 1.NP | Šatní skříňka s předlavičkou | 1465SEl0000024646
Šatní skříňka s předlavičkou | Půdorys 1.NP | Šatní skříňka s předlavičkou | 1465SEl0000024651
Šatní skříňka s předlavičkou | Půdorys 1.NP | Šatní skříňka s předlavičkou | 1465SEl0000024656
Šatní skříňka s předlavičkou | Půdorys 1.NP | Šatní skříňka s předlavičkou | 1465SEl0000024661
Šatní skříňka s předlavičkou | Půdorys 1.NP | Šatní skříňka s předlavičkou | 1465SEl0000024666
Šatní skříňka s předlavičkou | Půdorys 1.NP | Šatní skříňka s předlavičkou | 1465SEl0000024671
Šatní skříňka s předlavičkou | Půdorys 1.NP | Šatní skříňka s předlavičkou | 1465SEl0000024676
Šatní skříňka s předlavičkou | Půdorys 1.NP | Šatní skříňka s předlavičkou | 1465SEl0000024681
Šatní skříňka s předlavičkou | Půdorys 1.NP | Šatní skříňka s předlavičkou | 1465SEl0000024686
Šatní skříňka s předlavičkou | Půdorys 1.NP | Šatní skříňka s předlavičkou | 1465SEl0000024691
Šatní skříňka s předlavičkou | Půdorys 1.NP | Šatní skříňka s předlavičkou | 1465SEl0000024696
Šatní skříňka s předlavičkou | Půdorys 1.NP | Šatní skříňka s předlavičkou | 1465SEl0000024701
Šatní skříňka s předlavičkou | Půdorys 1.NP | Šatní skříňka s předlavičkou | 1465SEl0000024706
Šatní skříňka s předlavičkou | Půdorys 1.NP | Šatní skříňka s předlavičkou | 1465SEl0000024711
Šatní skříňka s předlavičkou | Půdorys 1.NP | Šatní skříňka s předlavičkou | 1465SEl0000024621
Šatní skříňka s předlavičkou | Půdorys 1.NP | Šatní skříňka s předlavičkou | 1465SEl0000024616
Šatní skříňka s předlavičkou | Půdorys 1.NP | Šatní skříňka s předlavičkou | 1465SEl0000024611
Šatní skříňka s předlavičkou | Půdorys 1.NP | Šatní skříňka s předlavičkou | 1465SEl0000024606
Šatní skříňka s předlavičkou | Půdorys 1.NP | Šatní skříňka s předlavičkou | 1465SEl0000024601
Šatní skříňka s předlavičkou | Půdorys 1.NP | Šatní skříňka s předlavičkou | 1465SEl0000024592
Šatní skříňka s předlavičkou | Půdorys 1.NP | Šatní skříňka s předlavičkou | 1465SEl0000024636
Šatní skříňka s předlavičkou | Půdorys 1.NP | Šatní skříňka s předlavičkou | 1465SEl0000024631
CHRLIČ TECE 110 BIT | Půdorys 6.NP |  | 1964SEl0000003452
CHRLIČ TECE 110 BIT | Půdorys 6.NP |  | 1964SEl0000003457
chrlič kulatý vyhří. TWCE 75 BIT | Půdorys střechy |  | 2481SEl0000000616
chrlič kulatý vyhří. TWCE 75 BIT | Půdorys střechy |  | 2481SEl0000000619

# IfcFooting (240)
NEMSOK - 2D interakce: yes; Práce: Betonářské práce; Jednotka: m3
Name | In | PredefinedType | Allright_Stavebni_dil_ID | Název_objektu | Status | LoadBearing | Length (m) | NetVolume (m3) | Width (m) | OuterSurfaceArea (m2) | Height (m) | GrossVolume (m3) | Material = Materiál | Kód prvku | Třída pevnosti ocele | Třída pevnosti betonu
 | Základy | STRIP_FOOTING | 0877ZPa0000000260 | Základový pás | EXISTING | no | 9.75 | 12.411 | 2.2 | 21.45 | 0.7 | 15.015
 | Základy | STRIP_FOOTING | 0877ZPa0000000254 | Základový pás | EXISTING | no | 3.65 | 5.22 | 1.1 | 4.015 | 1.3 | 5.22
 | Základy | STRIP_FOOTING | 0877ZPa0000000252 | Základový pás | EXISTING | no | 2.08 | 2.111 | 1.45 | 3.016 | 0.7 | 2.111
 | Základy | STRIP_FOOTING | 0877ZPa0000000250 | Základový pás | EXISTING | no | 4.05 | 3.969 | 1.4 | 5.67 | 0.7 | 3.969
 | Základy | STRIP_FOOTING | 0877ZPa0000000247 | Základový pás | EXISTING | no | 7 | 13.377 | 1.47 | 10.29 | 1.3 | 13.377
 | Základy | STRIP_FOOTING | 0877ZPa0000000245 | Základový pás | EXISTING | no | 1 | 2.86 | 2.2 | 2.2 | 1.3 | 2.86
 | Základy | STRIP_FOOTING | 0877ZPa0000000242 | Základový pás | EXISTING | no | 3.7 | 4.39 | 1.695 | 6.272 | 0.7 | 4.39
 | Základy | STRIP_FOOTING | 0877ZPa0000000240 | Základový pás | EXISTING | no | 1 | 2.86 | 2.2 | 2.2 | 1.3 | 2.86
 | Základy | STRIP_FOOTING | 0877ZPa0000000233 | Základový pás | EXISTING | no | 1.35 | 1.602 | 1.695 | 2.288 | 0.7 | 1.602
 | Základy | STRIP_FOOTING | 0877ZPa0000000231 | Základový pás | EXISTING | no | 3 | 2.94 | 1.4 | 4.2 | 0.7 | 2.94
 | Základy | STRIP_FOOTING | 0877ZPa0000000229 | Základový pás | EXISTING | no | 4.5 | 14.017 | 4.45 | 20.025 | 0.7 | 14.017
 | Základy | STRIP_FOOTING | 0877ZPa0000000227 | Základový pás | EXISTING | no | 2.35 | 1.316 | 0.8 | 1.88 | 0.7 | 1.316
 | Základy | STRIP_FOOTING | 0877ZPa0000000224 | Základový pás | EXISTING | no | 12 | 18.48 | 2.2 | 26.4 | 0.7 | 18.48
 | Základy | STRIP_FOOTING | 0877ZPa0000000222 | Základový pás | EXISTING | no | 6.2 | 9.548 | 2.2 | 13.64 | 0.7 | 9.548
 | Základy | STRIP_FOOTING | 0877ZPa0000000220 | Základový pás | EXISTING | no | 1 | 2.86 | 2.2 | 2.2 | 1.3 | 2.86
 | Základy | STRIP_FOOTING | 0877ZPa0000000218 | Základový pás | EXISTING | no | 12 | 18.48 | 2.2 | 26.4 | 0.7 | 18.48
 | Základy | STRIP_FOOTING | 0877ZPa0000000216 | Základový pás | EXISTING | no | 2.6 | 3.146 | 2.2 | 5.72 | 0.55 | 3.146
 | Základy | STRIP_FOOTING | 0877ZPa0000000214 | Základový pás | EXISTING | no | 2.6 | 3.146 | 2.2 | 5.72 | 0.55 | 3.146
 | Základy | STRIP_FOOTING | 0877ZPa0000000212 | Základový pás | EXISTING | no | 2.35 | 2.961 | 1.8 | 4.23 | 0.7 | 2.961
 | Základy | STRIP_FOOTING | 0877ZPa0000000210 | Základový pás | EXISTING | no | 10.9 | 38.685 | 5.07 | 55.264 | 0.7 | 38.685
 | Základy | STRIP_FOOTING | 0877ZPa0000000203 | Základový pás | EXISTING | no | 3.73 | 11.606 | 4.445 | 16.58 | 0.7 | 11.606
 | Základy | STRIP_FOOTING | 0877ZPa0000000201 | Základový pás | EXISTING | no | 7.45 | 7.301 | 1.4 | 10.43 | 0.7 | 7.301
 | Základy | STRIP_FOOTING | 0877ZPa0000000198 | Základový pás | EXISTING | no | 1.185 | 3.273 | 3.945 | 4.676 | 0.7 | 3.273
 | Základy | STRIP_FOOTING | 0877ZPa0000000194 | Základový pás | EXISTING | no | 6.03 | 9.286 | 2.2 | 13.266 | 0.7 | 9.286
 | Základy | STRIP_FOOTING | 0877ZPa0000000192 | Základový pás | EXISTING | no | 2.95 | 3.189 | 1.9 | 5.605 | 0.7 | 3.923
 | Základy | STRIP_FOOTING | 0877ZPa0000000189 | Základový pás | EXISTING | no | 3.65 | 4.271 | 0.9 | 3.285 | 1.3 | 4.271
 | Základy | STRIP_FOOTING | 0877ZPa0000000183 | Základový pás | EXISTING | no | 1 | 2.86 | 2.2 | 2.2 | 1.3 | 2.86
 | Základy | STRIP_FOOTING | 0877ZPa0000000180 | Základový pás | EXISTING | no | 2.708 | 2.748 | 1.45 | 3.926 | 0.7 | 2.748
 | Základy | STRIP_FOOTING | 0877ZPa0000000175 | Základový pás | EXISTING | no | 5 | 7.7 | 2.2 | 11 | 0.7 | 7.7
 | Základy | STRIP_FOOTING | 0877ZPa0000000170 | Základový pás | EXISTING | no | 1 | 2.86 | 2.2 | 2.2 | 1.3 | 2.86
 | Základy | STRIP_FOOTING | 0877ZPa0000000168 | Základový pás | EXISTING | no | 1 | 2.86 | 2.2 | 2.2 | 1.3 | 2.86
 | Základy | STRIP_FOOTING | 0877ZPa0000000166 | Základový pás | EXISTING | no | 8.6 | 13.244 | 2.2 | 18.92 | 0.7 | 13.244
 | Základy | STRIP_FOOTING | 0877ZPa0000000163 | Základový pás | EXISTING | no | 4.8 | 7.392 | 2.2 | 10.56 | 0.7 | 7.392
 | Základy | STRIP_FOOTING | 0877ZPa0000000157 | Základový pás | EXISTING | no | 2.8 | 4.312 | 2.2 | 6.16 | 0.7 | 4.312
 | Základy | STRIP_FOOTING | 0877ZPa0000000153 | Základový pás | EXISTING | no | 3.6 | 3.528 | 1.4 | 5.04 | 0.7 | 3.528
 | Základy | STRIP_FOOTING | 0877ZPa0000000151 | Základový pás | EXISTING | no | 5.446 | 6.1 | 1.6 | 8.714 | 0.7 | 6.1
 | Základy | STRIP_FOOTING | 0877ZPa0000000143 | Základový pás | EXISTING | no | 1.67 | 3.156 | 2.7 | 4.509 | 0.7 | 3.156
 | Základy | STRIP_FOOTING | 0877ZPa0000000129 | Základový pás | EXISTING | no | 11 | 16.94 | 2.2 | 24.2 | 0.7 | 16.94
 | Základy | STRIP_FOOTING | 0877ZPa0000000127 | Základový pás | EXISTING | no | 8.6 | 13.244 | 2.2 | 18.92 | 0.7 | 13.244
 | Základy | STRIP_FOOTING | 0877ZPa0000000123 | Základový pás | EXISTING | no | 1 | 2.86 | 2.2 | 2.2 | 1.3 | 2.86
 | Základy | STRIP_FOOTING | 0877ZPa0000000119 | Základový pás | EXISTING | no | 5.8 | 2.668 | 2.3 | 13.34 | 0.2 | 2.668
 | Základy | STRIP_FOOTING | 0877ZPa0000000116 | Základový pás | EXISTING | no | 3.7 | 4.144 | 1.6 | 5.92 | 0.7 | 4.144
 | Základy | STRIP_FOOTING | 0877ZPa0000000112 | Základový pás | EXISTING | no | 8.07 | 7.909 | 1.4 | 11.298 | 0.7 | 7.909
 | Základy | STRIP_FOOTING | 0877ZPa0000000108 | Základový pás | EXISTING | no | 26.239 | 49.683 | 2.705 | 70.976 | 0.7 | 49.683
 | Základy | STRIP_FOOTING | 0877ZPa0000000104 | Základový pás | EXISTING | no | 1 | 2.86 | 2.2 | 2.2 | 1.3 | 2.86
 | Základy | STRIP_FOOTING | 0877ZPa0000000100 | Základový pás | EXISTING | no | 8.6 | 13.244 | 2.2 | 18.92 | 0.7 | 13.244
 | Základy | STRIP_FOOTING | 0877ZPa0000000091 | Základový pás | EXISTING | no | 11.15 | 10.927 | 1.4 | 15.61 | 0.7 | 10.927
 | Základy | STRIP_FOOTING | 0877ZPa0000000089 | Základový pás | EXISTING | no | 3.135 | 3.072 | 1.4 | 4.389 | 0.7 | 3.072
 | Základy | STRIP_FOOTING | 0877ZPa0000000087 | Základový pás | EXISTING | no | 3.135 | 3.072 | 1.4 | 4.389 | 0.7 | 3.072
 | Základy | STRIP_FOOTING | 0877ZPa0000000085 | Základový pás | EXISTING | no | 3.125 | 3.063 | 1.4 | 4.375 | 0.7 | 3.063
 | Základy | STRIP_FOOTING | 0877ZPa0000000083 | Základový pás | EXISTING | no | 3.125 | 3.062 | 1.4 | 4.375 | 0.7 | 3.062
 | Základy | STRIP_FOOTING | 0877ZPa0000000081 | Základový pás | EXISTING | no | 12.85 | 12.593 | 1.4 | 17.99 | 0.7 | 12.593
 | Základy | STRIP_FOOTING | 0877ZPa0000000079 | Základový pás | EXISTING | no | 11.345 | 21.482 | 2.705 | 30.688 | 0.7 | 21.482
 | Základy | STRIP_FOOTING | 0877ZPa0000000077 | Základový pás | EXISTING | no | 11.345 | 21.482 | 2.705 | 30.688 | 0.7 | 21.482
 | Základy | STRIP_FOOTING | 0877ZPa0000000075 | Základový pás | EXISTING | no | 22.495 | 10.239 | 0.7 | 15.746 | 0.7 | 11.023
 | Základy | STRIP_FOOTING | 0877ZPa0000000065 | Základový pás | EXISTING | no | 3.74 | 3.665 | 1.4 | 5.236 | 0.7 | 3.665
 | Základy | STRIP_FOOTING | 0877ZPa0000000063 | Základový pás | EXISTING | no | 1 | 1.4 | 1.4 | 1.4 | 1 | 1.4
 | Základy | STRIP_FOOTING | 0877ZPa0000000060 | Základový pás | EXISTING | no | 1 | 1.4 | 1.4 | 1.4 | 1 | 1.4
 | Základy | STRIP_FOOTING | 0877ZPa0000000056 | Základový pás | EXISTING | no | 3.74 | 3.665 | 1.4 | 5.236 | 0.7 | 3.665
 | Základy | STRIP_FOOTING | 0877ZPa0000000054 | Základový pás | EXISTING | no | 1 | 1.68 | 1.4 | 1.4 | 1.2 | 1.68
 | Základy | STRIP_FOOTING | 0877ZPa0000000051 | Základový pás | EXISTING | no | 1 | 1.68 | 1.4 | 1.4 | 1.2 | 1.68
 | Základy | STRIP_FOOTING | 0877ZPa0000000047 | Základový pás | EXISTING | no | 3.74 | 3.665 | 1.4 | 5.236 | 0.7 | 3.665
 | Základy | STRIP_FOOTING | 0877ZPa0000000045 | Základový pás | EXISTING | no | 3.135 | 3.072 | 1.4 | 4.389 | 0.7 | 3.072
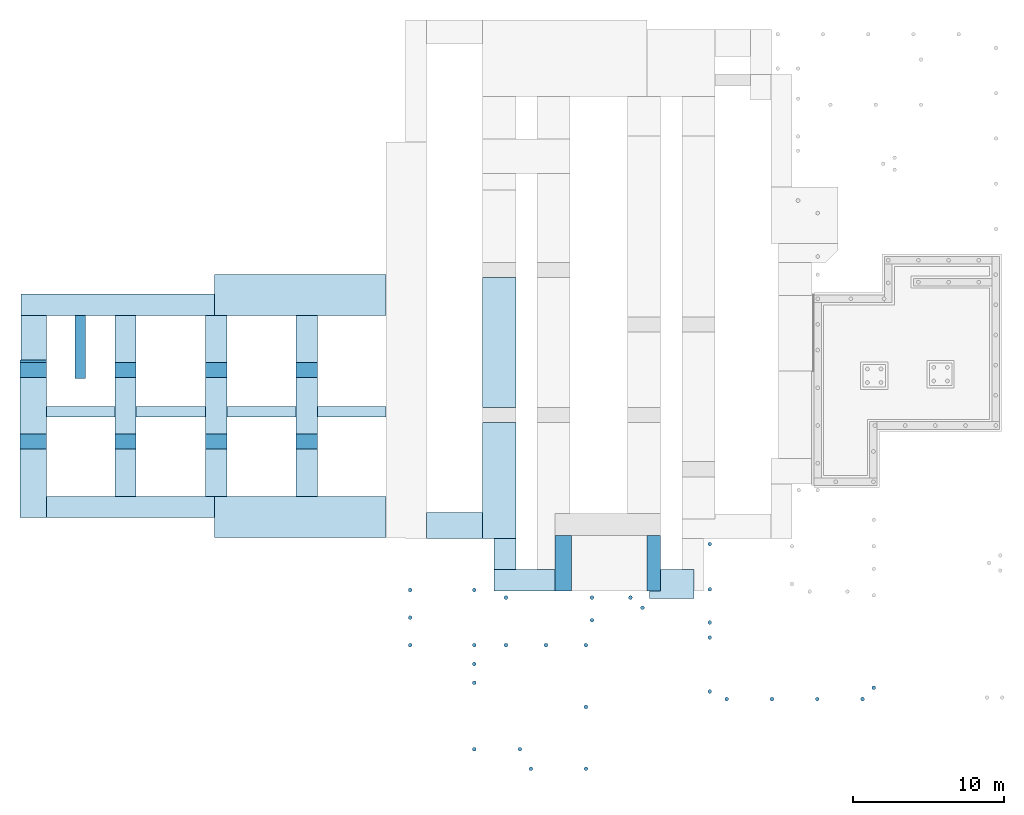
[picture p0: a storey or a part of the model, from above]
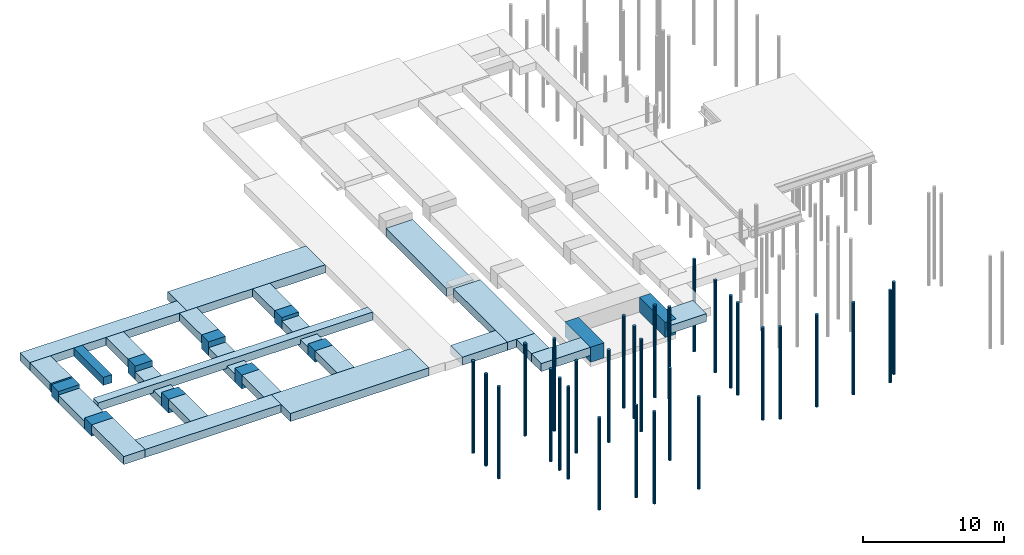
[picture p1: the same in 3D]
Properties of the parts of a building model (IFC4), part 12 of 45

# IfcFooting (240)
Name | In | PredefinedType | Allright_Stavebni_dil_ID | Název_objektu | Status | LoadBearing | Length (m) | NetVolume (m3) | Width (m) | OuterSurfaceArea (m2) | Height (m) | GrossVolume (m3) | Material = Materiál | Kód prvku | Třída pevnosti ocele | Třída pevnosti betonu
 | Základy | STRIP_FOOTING | 0877ZPa0000000043 | Základový pás | EXISTING | no | 1 | 1.68 | 1.4 | 1.4 | 1.2 | 1.68
 | Základy | STRIP_FOOTING | 0877ZPa0000000040 | Základový pás | EXISTING | no | 1 | 1.68 | 1.4 | 1.4 | 1.2 | 1.68
 | Základy | STRIP_FOOTING | 0877ZPa0000000037 | Základový pás | EXISTING | no | 3.125 | 3.062 | 1.4 | 4.375 | 0.7 | 3.062
 | Základy | STRIP_FOOTING | 0877ZPa0000000034 | Základový pás | EXISTING | no | 3.74 | 4.582 | 1.75 | 6.545 | 0.7 | 4.582
 | Základy | STRIP_FOOTING | 0877ZPa0000000032 | Základový pás | EXISTING | no | 4.535 | 5.555 | 1.75 | 7.936 | 0.7 | 5.555
 | Základy | STRIP_FOOTING | 0877ZPa0000000030 | Základový pás | EXISTING | no | 1 | 1.75 | 1.75 | 1.75 | 1 | 1.75
 | Základy | STRIP_FOOTING | 0877ZPa0000000027 | Základový pás | EXISTING | no | 1 | 1.75 | 1.75 | 1.75 | 1 | 1.75
 | Základy | STRIP_FOOTING | 0877ZPa0000000024 | Základový pás | EXISTING | no | 0.15 | 0.184 | 1.75 | 0.263 | 0.7 | 0.184
 | Základy | STRIP_FOOTING | 0877ZPa0000000014 | Základový pás | EXISTING | no | 2.975 | 3.54 | 1.7 | 5.058 | 0.7 | 3.54
 | Základy | STRIP_FOOTING | 0877ZPa0000000006 | Základový pás | EXISTING | no | 4.2 | 2.058 | 0.7 | 2.94 | 0.7 | 2.058
 | Základy | STRIP_FOOTING | 0877ZPa0000000145 | Základový pás | EXISTING | no | 5 | 8.067 | 2.305 | 11.525 | 0.7 | 8.067
 | Základy | STRIP_FOOTING | 0877ZPa0000000136 | Základový pás | EXISTING | no | 2.2 | 3.388 | 2.2 | 4.84 | 0.7 | 3.388
 | Základy | STRIP_FOOTING | 0877ZPa0000000141 | Základový pás | EXISTING | no | 5.8 | 8.932 | 2.2 | 12.76 | 0.7 | 8.932
 | Základy | STRIP_FOOTING | 0877ZPa0000000262 | Základový pás | EXISTING | no | 7.67 | 11.812 | 2.2 | 16.874 | 0.7 | 11.812
 | Základy | PAD_FOOTING | 0881SZa0000000267 | Základová patka | NEW | yes | 1.5 | 1.125 | 1.5 | 2.25 | 0.5 | 1.125 | ZELEZOBETONOVÁ KCE | ZP02.01.0001 | B500B | C25/30-XC2,XA1 | NEMSOK - Stupeň vyztužení: 70; Krytí výztuže: 50mm
 | Základy | STRIP_FOOTING | 0881ZPa0000000008 | Základový pás | NEW | yes | 4.195 | 1.049 | 0.5 | 2.097 | 0.5 | 1.049 | ZELEZOBETONOVÁ KCE | ZP02.01.0003 | B500B | C25/30-XC2,XA1 | NEMSOK - Stupeň vyztužení: 70; Krytí výztuže: 50mm
 | Základy | STRIP_FOOTING | 0881ZPa0000000012 | Základový pás | NEW | yes | 3.72 | 0.93 | 0.5 | 1.86 | 0.5 | 0.93 | ZELEZOBETONOVÁ KCE | ZP02.01.0004 | B500B | C25/30-XC2,XA1 | NEMSOK - Stupeň vyztužení: 70; Krytí výztuže: 50mm
 | Základy | STRIP_FOOTING | 0881ZPa0000000022 | Základový pás | NEW | yes | 8.1 | 2.025 | 0.5 | 4.05 | 0.5 | 2.025 | ZELEZOBETONOVÁ KCE | ZP02.01.0005 | B500B | C25/30-XC2,XA1 | NEMSOK - Stupeň vyztužení: 70; Krytí výztuže: 50mm
 | Základy | STRIP_FOOTING | 0881ZPa0000000034 | Základový pás | NEW | yes | 10.95 | 2.737 | 0.5 | 5.475 | 0.5 | 2.737 | ZELEZOBETONOVÁ KCE | ZP02.01.0006 | B500B | C25/30-XC2,XA1 | NEMSOK - Stupeň vyztužení: 70; Krytí výztuže: 50mm
 | Základy | STRIP_FOOTING | 0881ZPa0000000046 | Základový pás | NEW | yes | 7.121 | 1.78 | 0.5 | 3.561 | 0.5 | 1.78 | ZELEZOBETONOVÁ KCE | ZP02.01.0007 | B500B | C25/30-XC2,XA1 | NEMSOK - Stupeň vyztužení: 70; Krytí výztuže: 50mm
 | Základy | STRIP_FOOTING | 0881ZPa0000000058 | Základový pás | NEW | yes | 2.55 | 0.637 | 0.5 | 1.275 | 0.5 | 0.637 | ZELEZOBETONOVÁ KCE | ZP02.01.0008 | B500B | C25/30-XC2,XA1 | NEMSOK - Stupeň vyztužení: 70; Krytí výztuže: 50mm
 | Základy | STRIP_FOOTING | 0881ZPa0000000070 | Základový pás | NEW | yes | 4.674 | 1.168 | 0.5 | 2.337 | 0.5 | 1.168 | ZELEZOBETONOVÁ KCE | ZP02.01.0009 | B500B | C25/30-XC2,XA1 | NEMSOK - Stupeň vyztužení: 70; Krytí výztuže: 50mm
 | Základy | STRIP_FOOTING | 0881ZPa0000000138 | Základový pás | NEW | yes | 11.62 | 2.905 | 0.5 | 5.81 | 0.5 | 2.905 | ZELEZOBETONOVÁ KCE | ZP02.01.0010 | B500B | C25/30-XC2,XA1 | NEMSOK - Stupeň vyztužení: 70; Krytí výztuže: 50mm
 | Základy | STRIP_FOOTING | 0881ZPa0000000211 | Základový pás | NEW | yes | 5.2 | 1.3 | 0.5 | 2.6 | 0.5 | 1.3 | ZELEZOBETONOVÁ KCE | ZP02.01.0011 | B500B | C25/30-XC2,XA1 | NEMSOK - Stupeň vyztužení: 70; Krytí výztuže: 50mm
 | Základy | PAD_FOOTING | 0881SZa0000000276 | Základová patka | NEW | yes | 1.5 | 1.125 | 1.5 | 2.25 | 0.5 | 1.125 | ZELEZOBETONOVÁ KCE | ZP02.01.0002 | B500B | C25/30-XC2,XA1 | NEMSOK - Stupeň vyztužení: 70; Krytí výztuže: 50mm
MIKROPILOTA MP2 | Základy | PAD_FOOTING | 0885SZa0000013841 | Mikropilota MP2 | NEW |  | 0.249 | 0.27 | 0.197 | 0.049 | 5.5 | 0.27 | ZELEZOBETONOVÁ KCE | MP02.01.0001 | S 355 | C 20/25 | NEMSOK - Označení: MIKROPILOTA MP2; Průměr (2): 250; Délka kořene: 5000; Druh výztuže: TR 108/10
MIKROPILOTA MP2 | Základy | PAD_FOOTING | 0885SZa0000013886 | Mikropilota MP2 | NEW |  | 0.249 | 0.27 | 0.197 | 0.049 | 5.5 | 0.27 | ZELEZOBETONOVÁ KCE | MP02.01.0002 | S 355 | C 20/25 | NEMSOK - Označení: MIKROPILOTA MP2; Průměr (2): 250; Délka kořene: 5000; Druh výztuže: TR 108/10
MIKROPILOTA MP2 | Základy | PAD_FOOTING | 0885SZa0000013887 | Mikropilota MP2 | NEW |  | 0.249 | 0.27 | 0.197 | 0.049 | 5.5 | 0.27 | ZELEZOBETONOVÁ KCE | MP02.01.0003 | S 355 | C 20/25 | NEMSOK - Označení: MIKROPILOTA MP2; Průměr (2): 250; Délka kořene: 5000; Druh výztuže: TR 108/10
MIKROPILOTA MP2 | Základy | PAD_FOOTING | 0885SZa0000013888 | Mikropilota MP2 | NEW |  | 0.249 | 0.27 | 0.197 | 0.049 | 5.5 | 0.27 | ZELEZOBETONOVÁ KCE | MP02.01.0004 | S 355 | C 20/25 | NEMSOK - Označení: MIKROPILOTA MP2; Průměr (2): 250; Délka kořene: 5000; Druh výztuže: TR 108/10
MIKROPILOTA MP2 | Základy | PAD_FOOTING | 0885SZa0000013889 | Mikropilota MP2 | NEW |  | 0.249 | 0.27 | 0.197 | 0.049 | 5.5 | 0.27 | ZELEZOBETONOVÁ KCE | MP02.01.0005 | S 355 | C 20/25 | NEMSOK - Označení: MIKROPILOTA MP2; Průměr (2): 250; Délka kořene: 5000; Druh výztuže: TR 108/10
MIKROPILOTA MP2 | Základy | PAD_FOOTING | 0885SZa0000013890 | Mikropilota MP2 | NEW |  | 0.249 | 0.27 | 0.197 | 0.049 | 5.5 | 0.27 | ZELEZOBETONOVÁ KCE | MP02.01.0006 | S 355 | C 20/25 | NEMSOK - Označení: MIKROPILOTA MP2; Průměr (2): 250; Délka kořene: 5000; Druh výztuže: TR 108/10
MIKROPILOTA MP2 | Základy | PAD_FOOTING | 0885SZa0000013891 | Mikropilota MP2 | NEW |  | 0.249 | 0.27 | 0.197 | 0.049 | 5.5 | 0.27 | ZELEZOBETONOVÁ KCE | MP02.01.0007 | S 355 | C 20/25 | NEMSOK - Označení: MIKROPILOTA MP2; Průměr (2): 250; Délka kořene: 5000; Druh výztuže: TR 108/10
MIKROPILOTA MP2 | Základy | PAD_FOOTING | 0885SZa0000013892 | Mikropilota MP2 | NEW |  | 0.249 | 0.27 | 0.197 | 0.049 | 5.5 | 0.27 | ZELEZOBETONOVÁ KCE | MP02.01.0008 | S 355 | C 20/25 | NEMSOK - Označení: MIKROPILOTA MP2; Průměr (2): 250; Délka kořene: 5000; Druh výztuže: TR 108/10
MIKROPILOTA MP2 | Základy | PAD_FOOTING | 0885SZa0000013893 | Mikropilota MP2 | NEW |  | 0.249 | 0.27 | 0.197 | 0.049 | 5.5 | 0.27 | ZELEZOBETONOVÁ KCE | MP02.01.0009 | S 355 | C 20/25 | NEMSOK - Označení: MIKROPILOTA MP2; Průměr (2): 250; Délka kořene: 5000; Druh výztuže: TR 108/10
MIKROPILOTA MP2 | Základy | PAD_FOOTING | 0885SZa0000013894 | Mikropilota MP2 | NEW |  | 0.249 | 0.27 | 0.197 | 0.049 | 5.5 | 0.27 | ZELEZOBETONOVÁ KCE | MP02.01.0010 | S 355 | C 20/25 | NEMSOK - Označení: MIKROPILOTA MP2; Průměr (2): 250; Délka kořene: 5000; Druh výztuže: TR 108/10
MIKROPILOTA MP2 | Základy | PAD_FOOTING | 0885SZa0000013895 | Mikropilota MP2 | NEW |  | 0.249 | 0.27 | 0.197 | 0.049 | 5.5 | 0.27 | ZELEZOBETONOVÁ KCE | MP02.01.0011 | S 355 | C 20/25 | NEMSOK - Označení: MIKROPILOTA MP2; Průměr (2): 250; Délka kořene: 5000; Druh výztuže: TR 108/10
MIKROPILOTA MP2 | Základy | PAD_FOOTING | 0885SZa0000013896 | Mikropilota MP2 | NEW |  | 0.249 | 0.27 | 0.197 | 0.049 | 5.5 | 0.27 | ZELEZOBETONOVÁ KCE | MP02.01.0012 | S 355 | C 20/25 | NEMSOK - Označení: MIKROPILOTA MP2; Průměr (2): 250; Délka kořene: 5000; Druh výztuže: TR 108/10
MIKROPILOTA MP2 | Základy | PAD_FOOTING | 0885SZa0000013897 | Mikropilota MP2 | NEW |  | 0.249 | 0.27 | 0.197 | 0.049 | 5.5 | 0.27 | ZELEZOBETONOVÁ KCE | MP02.01.0013 | S 355 | C 20/25 | NEMSOK - Označení: MIKROPILOTA MP2; Průměr (2): 250; Délka kořene: 5000; Druh výztuže: TR 108/10
MIKROPILOTA MP2 | Základy | PAD_FOOTING | 0885SZa0000013898 | Mikropilota MP2 | NEW |  | 0.249 | 0.27 | 0.197 | 0.049 | 5.5 | 0.27 | ZELEZOBETONOVÁ KCE | MP02.01.0014 | S 355 | C 20/25 | NEMSOK - Označení: MIKROPILOTA MP2; Průměr (2): 250; Délka kořene: 5000; Druh výztuže: TR 108/10
MIKROPILOTA MP2 | Základy | PAD_FOOTING | 0885SZa0000013899 | Mikropilota MP2 | NEW |  | 0.249 | 0.27 | 0.197 | 0.049 | 5.5 | 0.27 | ZELEZOBETONOVÁ KCE | MP02.01.0015 | S 355 | C 20/25 | NEMSOK - Označení: MIKROPILOTA MP2; Průměr (2): 250; Délka kořene: 5000; Druh výztuže: TR 108/10
MIKROPILOTA MP2 | Základy | PAD_FOOTING | 0885SZa0000013900 | Mikropilota MP2 | NEW |  | 0.249 | 0.27 | 0.197 | 0.049 | 5.5 | 0.27 | ZELEZOBETONOVÁ KCE | MP02.01.0016 | S 355 | C 20/25 | NEMSOK - Označení: MIKROPILOTA MP2; Průměr (2): 250; Délka kořene: 5000; Druh výztuže: TR 108/10
MIKROPILOTA MP2 | Základy | PAD_FOOTING | 0885SZa0000013901 | Mikropilota MP2 | NEW |  | 0.249 | 0.27 | 0.197 | 0.049 | 5.5 | 0.27 | ZELEZOBETONOVÁ KCE | MP02.01.0017 | S 355 | C 20/25 | NEMSOK - Označení: MIKROPILOTA MP2; Průměr (2): 250; Délka kořene: 5000; Druh výztuže: TR 108/10
MIKROPILOTA MP2 | Základy | PAD_FOOTING | 0885SZa0000013902 | Mikropilota MP2 | NEW |  | 0.249 | 0.27 | 0.197 | 0.049 | 5.5 | 0.27 | ZELEZOBETONOVÁ KCE | MP02.01.0018 | S 355 | C 20/25 | NEMSOK - Označení: MIKROPILOTA MP2; Průměr (2): 250; Délka kořene: 5000; Druh výztuže: TR 108/10
MIKROPILOTA MP2 | Základy | PAD_FOOTING | 0885SZa0000013903 | Mikropilota MP2 | NEW |  | 0.249 | 0.27 | 0.197 | 0.049 | 5.5 | 0.27 | ZELEZOBETONOVÁ KCE | MP02.01.0019 | S 355 | C 20/25 | NEMSOK - Označení: MIKROPILOTA MP2; Průměr (2): 250; Délka kořene: 5000; Druh výztuže: TR 108/10
MIKROPILOTA MP2 | Základy | PAD_FOOTING | 0885SZa0000013904 | Mikropilota MP2 | NEW |  | 0.249 | 0.27 | 0.197 | 0.049 | 5.5 | 0.27 | ZELEZOBETONOVÁ KCE | MP02.01.0020 | S 355 | C 20/25 | NEMSOK - Označení: MIKROPILOTA MP2; Průměr (2): 250; Délka kořene: 5000; Druh výztuže: TR 108/10
MIKROPILOTA MP2 | Základy | PAD_FOOTING | 0885SZa0000013905 | Mikropilota MP2 | NEW |  | 0.249 | 0.27 | 0.197 | 0.049 | 5.5 | 0.27 | ZELEZOBETONOVÁ KCE | MP02.01.0021 | S 355 | C 20/25 | NEMSOK - Označení: MIKROPILOTA MP2; Průměr (2): 250; Délka kořene: 5000; Druh výztuže: TR 108/10
MIKROPILOTA MP2 | Základy | PAD_FOOTING | 0885SZa0000013906 | Mikropilota MP2 | NEW |  | 0.249 | 0.27 | 0.197 | 0.049 | 5.5 | 0.27 | ZELEZOBETONOVÁ KCE | MP02.01.0022 | S 355 | C 20/25 | NEMSOK - Označení: MIKROPILOTA MP2; Průměr (2): 250; Délka kořene: 5000; Druh výztuže: TR 108/10
MIKROPILOTA MP2 | Základy | PAD_FOOTING | 0885SZa0000013907 | Mikropilota MP2 | NEW |  | 0.249 | 0.27 | 0.197 | 0.049 | 5.5 | 0.27 | ZELEZOBETONOVÁ KCE | MP02.01.0023 | S 355 | C 20/25 | NEMSOK - Označení: MIKROPILOTA MP2; Průměr (2): 250; Délka kořene: 5000; Druh výztuže: TR 108/10
MIKROPILOTA MP2 | Základy | PAD_FOOTING | 0885SZa0000013908 | Mikropilota MP2 | NEW |  | 0.249 | 0.27 | 0.197 | 0.049 | 5.5 | 0.27 | ZELEZOBETONOVÁ KCE | MP02.01.0024 | S 355 | C 20/25 | NEMSOK - Označení: MIKROPILOTA MP2; Průměr (2): 250; Délka kořene: 5000; Druh výztuže: TR 108/10
MIKROPILOTA MP2 | Základy | PAD_FOOTING | 0885SZa0000013909 | Mikropilota MP2 | NEW |  | 0.249 | 0.27 | 0.197 | 0.049 | 5.5 | 0.27 | ZELEZOBETONOVÁ KCE | MP02.01.0025 | S 355 | C 20/25 | NEMSOK - Označení: MIKROPILOTA MP2; Průměr (2): 250; Délka kořene: 5000; Druh výztuže: TR 108/10
MIKROPILOTA MP2 | Základy | PAD_FOOTING | 0885SZa0000013910 | Mikropilota MP2 | NEW |  | 0.249 | 0.27 | 0.197 | 0.049 | 5.5 | 0.27 | ZELEZOBETONOVÁ KCE | MP02.01.0026 | S 355 | C 20/25 | NEMSOK - Označení: MIKROPILOTA MP2; Průměr (2): 250; Délka kořene: 5000; Druh výztuže: TR 108/10
MIKROPILOTA MP2 | Základy | PAD_FOOTING | 0885SZa0000013911 | Mikropilota MP2 | NEW |  | 0.249 | 0.27 | 0.197 | 0.049 | 5.5 | 0.27 | ZELEZOBETONOVÁ KCE | MP02.01.0027 | S 355 | C 20/25 | NEMSOK - Označení: MIKROPILOTA MP2; Průměr (2): 250; Délka kořene: 5000; Druh výztuže: TR 108/10
MIKROPILOTA MP2 | Základy | PAD_FOOTING | 0885SZa0000013912 | Mikropilota MP2 | NEW |  | 0.249 | 0.27 | 0.197 | 0.049 | 5.5 | 0.27 | ZELEZOBETONOVÁ KCE | MP02.01.0028 | S 355 | C 20/25 | NEMSOK - Označení: MIKROPILOTA MP2; Průměr (2): 250; Délka kořene: 5000; Druh výztuže: TR 108/10
MIKROPILOTA MP2 | Základy | PAD_FOOTING | 0885SZa0000013913 | Mikropilota MP2 | NEW |  | 0.249 | 0.27 | 0.197 | 0.049 | 5.5 | 0.27 | ZELEZOBETONOVÁ KCE | MP02.01.0029 | S 355 | C 20/25 | NEMSOK - Označení: MIKROPILOTA MP2; Průměr (2): 250; Délka kořene: 5000; Druh výztuže: TR 108/10
MIKROPILOTA MP2 | Základy | PAD_FOOTING | 0885SZa0000013914 | Mikropilota MP2 | NEW |  | 0.249 | 0.27 | 0.197 | 0.049 | 5.5 | 0.27 | ZELEZOBETONOVÁ KCE | MP02.01.0030 | S 355 | C 20/25 | NEMSOK - Označení: MIKROPILOTA MP2; Průměr (2): 250; Délka kořene: 5000; Druh výztuže: TR 108/10
MIKROPILOTA MP2 | Základy | PAD_FOOTING | 0885SZa0000013915 | Mikropilota MP2 | NEW |  | 0.249 | 0.27 | 0.197 | 0.049 | 5.5 | 0.27 | ZELEZOBETONOVÁ KCE | MP02.01.0031 | S 355 | C 20/25 | NEMSOK - Označení: MIKROPILOTA MP2; Průměr (2): 250; Délka kořene: 5000; Druh výztuže: TR 108/10
MIKROPILOTA MP2 | Základy | PAD_FOOTING | 0885SZa0000013916 | Mikropilota MP2 | NEW |  | 0.249 | 0.27 | 0.197 | 0.049 | 5.5 | 0.27 | ZELEZOBETONOVÁ KCE | MP02.01.0032 | S 355 | C 20/25 | NEMSOK - Označení: MIKROPILOTA MP2; Průměr (2): 250; Délka kořene: 5000; Druh výztuže: TR 108/10
MIKROPILOTA MP2 | Základy | PAD_FOOTING | 0885SZa0000013917 | Mikropilota MP2 | NEW |  | 0.249 | 0.27 | 0.197 | 0.049 | 5.5 | 0.27 | ZELEZOBETONOVÁ KCE | MP02.01.0033 | S 355 | C 20/25 | NEMSOK - Označení: MIKROPILOTA MP2; Průměr (2): 250; Délka kořene: 5000; Druh výztuže: TR 108/10
MIKROPILOTA MP2 | Základy | PAD_FOOTING | 0885SZa0000013918 | Mikropilota MP2 | NEW |  | 0.249 | 0.27 | 0.197 | 0.049 | 5.5 | 0.27 | ZELEZOBETONOVÁ KCE | MP02.01.0034 | S 355 | C 20/25 | NEMSOK - Označení: MIKROPILOTA MP2; Průměr (2): 250; Délka kořene: 5000; Druh výztuže: TR 108/10
MIKROPILOTA MP2 | Základy | PAD_FOOTING | 0885SZa0000013919 | Mikropilota MP2 | NEW |  | 0.249 | 0.27 | 0.197 | 0.049 | 5.5 | 0.27 | ZELEZOBETONOVÁ KCE | MP02.01.0035 | S 355 | C 20/25 | NEMSOK - Označení: MIKROPILOTA MP2; Průměr (2): 250; Délka kořene: 5000; Druh výztuže: TR 108/10
MIKROPILOTA MP2 | Základy | PAD_FOOTING | 0885SZa0000013921 | Mikropilota MP2 | NEW |  | 0.249 | 0.27 | 0.197 | 0.049 | 5.5 | 0.27 | ZELEZOBETONOVÁ KCE | MP02.01.0036 | S 355 | C 20/25 | NEMSOK - Označení: MIKROPILOTA MP2; Průměr (2): 250; Délka kořene: 5000; Druh výztuže: TR 108/10
MIKROPILOTA MP2 | Základy | PAD_FOOTING | 0885SZa0000013922 | Mikropilota MP2 | NEW |  | 0.249 | 0.27 | 0.197 | 0.049 | 5.5 | 0.27 | ZELEZOBETONOVÁ KCE | MP02.01.0037 | S 355 | C 20/25 | NEMSOK - Označení: MIKROPILOTA MP2; Průměr (2): 250; Délka kořene: 5000; Druh výztuže: TR 108/10
MIKROPILOTA MP1 | Základy | PAD_FOOTING | 0886SZa0000028152 | Mikropilota MP1 | NEW |  | 0.249 | 0.393 | 0.197 | 0.049 | 8 | 0.393 | ZELEZOBETONOVÁ KCE | MP02.02.0001 | S 355 | C 20/25 | NEMSOK - Označení: MIKROPILOTA MP1; Průměr (2): 250; Délka kořene: 8000; Druh výztuže: TR 108/10
MIKROPILOTA MP1 | Základy | PAD_FOOTING | 0886SZa0000028647 | Mikropilota MP1 | NEW |  | 0.249 | 0.393 | 0.197 | 0.049 | 8 | 0.393 | ZELEZOBETONOVÁ KCE | MP02.02.0002 | S 355 | C 20/25 | NEMSOK - Označení: MIKROPILOTA MP1; Průměr (2): 250; Délka kořene: 8000; Druh výztuže: TR 108/10
MIKROPILOTA MP1 | Základy | PAD_FOOTING | 0886SZa0000028648 | Mikropilota MP1 | NEW |  | 0.249 | 0.393 | 0.197 | 0.049 | 8 | 0.393 | ZELEZOBETONOVÁ KCE | MP02.02.0003 | S 355 | C 20/25 | NEMSOK - Označení: MIKROPILOTA MP1; Průměr (2): 250; Délka kořene: 8000; Druh výztuže: TR 108/10
MIKROPILOTA MP1 | Základy | PAD_FOOTING | 0886SZa0000028649 | Mikropilota MP1 | NEW |  | 0.249 | 0.393 | 0.197 | 0.049 | 8 | 0.393 | ZELEZOBETONOVÁ KCE | MP02.02.0004 | S 355 | C 20/25 | NEMSOK - Označení: MIKROPILOTA MP1; Průměr (2): 250; Délka kořene: 8000; Druh výztuže: TR 108/10
MIKROPILOTA MP1 | Základy | PAD_FOOTING | 0886SZa0000028650 | Mikropilota MP1 | NEW |  | 0.249 | 0.393 | 0.197 | 0.049 | 8 | 0.393 | ZELEZOBETONOVÁ KCE | MP02.02.0005 | S 355 | C 20/25 | NEMSOK - Označení: MIKROPILOTA MP1; Průměr (2): 250; Délka kořene: 8000; Druh výztuže: TR 108/10
MIKROPILOTA MP1 | Základy | PAD_FOOTING | 0886SZa0000028651 | Mikropilota MP1 | NEW |  | 0.249 | 0.393 | 0.197 | 0.049 | 8 | 0.393 | ZELEZOBETONOVÁ KCE | MP02.02.0006 | S 355 | C 20/25 | NEMSOK - Označení: MIKROPILOTA MP1; Průměr (2): 250; Délka kořene: 8000; Druh výztuže: TR 108/10
MIKROPILOTA MP1 | Základy | PAD_FOOTING | 0886SZa0000028652 | Mikropilota MP1 | NEW |  | 0.249 | 0.393 | 0.197 | 0.049 | 8 | 0.393 | ZELEZOBETONOVÁ KCE | MP02.02.0007 | S 355 | C 20/25 | NEMSOK - Označení: MIKROPILOTA MP1; Průměr (2): 250; Délka kořene: 8000; Druh výztuže: TR 108/10
MIKROPILOTA MP1 | Základy | PAD_FOOTING | 0886SZa0000028653 | Mikropilota MP1 | NEW |  | 0.249 | 0.393 | 0.197 | 0.049 | 8 | 0.393 | ZELEZOBETONOVÁ KCE | MP02.02.0008 | S 355 | C 20/25 | NEMSOK - Označení: MIKROPILOTA MP1; Průměr (2): 250; Délka kořene: 8000; Druh výztuže: TR 108/10
MIKROPILOTA MP1 | Základy | PAD_FOOTING | 0886SZa0000028654 | Mikropilota MP1 | NEW |  | 0.249 | 0.393 | 0.197 | 0.049 | 8 | 0.393 | ZELEZOBETONOVÁ KCE | MP02.02.0009 | S 355 | C 20/25 | NEMSOK - Označení: MIKROPILOTA MP1; Průměr (2): 250; Délka kořene: 8000; Druh výztuže: TR 108/10
MIKROPILOTA MP1 | Základy | PAD_FOOTING | 0886SZa0000028655 | Mikropilota MP1 | NEW |  | 0.249 | 0.393 | 0.197 | 0.049 | 8 | 0.393 | ZELEZOBETONOVÁ KCE | MP02.02.0010 | S 355 | C 20/25 | NEMSOK - Označení: MIKROPILOTA MP1; Průměr (2): 250; Délka kořene: 8000; Druh výztuže: TR 108/10
MIKROPILOTA MP1 | Základy | PAD_FOOTING | 0886SZa0000028656 | Mikropilota MP1 | NEW |  | 0.249 | 0.393 | 0.197 | 0.049 | 8 | 0.393 | ZELEZOBETONOVÁ KCE | MP02.02.0011 | S 355 | C 20/25 | NEMSOK - Označení: MIKROPILOTA MP1; Průměr (2): 250; Délka kořene: 8000; Druh výztuže: TR 108/10
MIKROPILOTA MP1 | Základy | PAD_FOOTING | 0886SZa0000028657 | Mikropilota MP1 | NEW |  | 0.249 | 0.393 | 0.197 | 0.049 | 8 | 0.393 | ZELEZOBETONOVÁ KCE | MP02.02.0012 | S 355 | C 20/25 | NEMSOK - Označení: MIKROPILOTA MP1; Průměr (2): 250; Délka kořene: 8000; Druh výztuže: TR 108/10
MIKROPILOTA MP1 | Základy | PAD_FOOTING | 0886SZa0000028658 | Mikropilota MP1 | NEW |  | 0.249 | 0.393 | 0.197 | 0.049 | 8 | 0.393 | ZELEZOBETONOVÁ KCE | MP02.02.0013 | S 355 | C 20/25 | NEMSOK - Označení: MIKROPILOTA MP1; Průměr (2): 250; Délka kořene: 8000; Druh výztuže: TR 108/10
MIKROPILOTA MP1 | Základy | PAD_FOOTING | 0886SZa0000028659 | Mikropilota MP1 | NEW |  | 0.249 | 0.393 | 0.197 | 0.049 | 8 | 0.393 | ZELEZOBETONOVÁ KCE | MP02.02.0014 | S 355 | C 20/25 | NEMSOK - Označení: MIKROPILOTA MP1; Průměr (2): 250; Délka kořene: 8000; Druh výztuže: TR 108/10
MIKROPILOTA MP1 | Základy | PAD_FOOTING | 0886SZa0000028660 | Mikropilota MP1 | NEW |  | 0.249 | 0.393 | 0.197 | 0.049 | 8 | 0.393 | ZELEZOBETONOVÁ KCE | MP02.02.0015 | S 355 | C 20/25 | NEMSOK - Označení: MIKROPILOTA MP1; Průměr (2): 250; Délka kořene: 8000; Druh výztuže: TR 108/10
MIKROPILOTA MP1 | Základy | PAD_FOOTING | 0886SZa0000028661 | Mikropilota MP1 | NEW |  | 0.249 | 0.393 | 0.197 | 0.049 | 8 | 0.393 | ZELEZOBETONOVÁ KCE | MP02.02.0016 | S 355 | C 20/25 | NEMSOK - Označení: MIKROPILOTA MP1; Průměr (2): 250; Délka kořene: 8000; Druh výztuže: TR 108/10
MIKROPILOTA MP1 | Základy | PAD_FOOTING | 0886SZa0000028662 | Mikropilota MP1 | NEW |  | 0.249 | 0.393 | 0.197 | 0.049 | 8 | 0.393 | ZELEZOBETONOVÁ KCE | MP02.02.0017 | S 355 | C 20/25 | NEMSOK - Označení: MIKROPILOTA MP1; Průměr (2): 250; Délka kořene: 8000; Druh výztuže: TR 108/10
MIKROPILOTA MP1 | Základy | PAD_FOOTING | 0886SZa0000028663 | Mikropilota MP1 | NEW |  | 0.249 | 0.393 | 0.197 | 0.049 | 8 | 0.393 | ZELEZOBETONOVÁ KCE | MP02.02.0018 | S 355 | C 20/25 | NEMSOK - Označení: MIKROPILOTA MP1; Průměr (2): 250; Délka kořene: 8000; Druh výztuže: TR 108/10
MIKROPILOTA MP1 | Základy | PAD_FOOTING | 0886SZa0000028664 | Mikropilota MP1 | NEW |  | 0.249 | 0.393 | 0.197 | 0.049 | 8 | 0.393 | ZELEZOBETONOVÁ KCE | MP02.02.0019 | S 355 | C 20/25 | NEMSOK - Označení: MIKROPILOTA MP1; Průměr (2): 250; Délka kořene: 8000; Druh výztuže: TR 108/10
MIKROPILOTA MP1 | Základy | PAD_FOOTING | 0886SZa0000028665 | Mikropilota MP1 | NEW |  | 0.249 | 0.393 | 0.197 | 0.049 | 8 | 0.393 | ZELEZOBETONOVÁ KCE | MP02.02.0020 | S 355 | C 20/25 | NEMSOK - Označení: MIKROPILOTA MP1; Průměr (2): 250; Délka kořene: 8000; Druh výztuže: TR 108/10
MIKROPILOTA MP1 | Základy | PAD_FOOTING | 0886SZa0000028666 | Mikropilota MP1 | NEW |  | 0.249 | 0.393 | 0.197 | 0.049 | 8 | 0.393 | ZELEZOBETONOVÁ KCE | MP02.02.0021 | S 355 | C 20/25 | NEMSOK - Označení: MIKROPILOTA MP1; Průměr (2): 250; Délka kořene: 8000; Druh výztuže: TR 108/10
MIKROPILOTA MP1 | Základy | PAD_FOOTING | 0886SZa0000028667 | Mikropilota MP1 | NEW |  | 0.249 | 0.393 | 0.197 | 0.049 | 8 | 0.393 | ZELEZOBETONOVÁ KCE | MP02.02.0022 | S 355 | C 20/25 | NEMSOK - Označení: MIKROPILOTA MP1; Průměr (2): 250; Délka kořene: 8000; Druh výztuže: TR 108/10
MIKROPILOTA MP1 | Základy | PAD_FOOTING | 0886SZa0000028668 | Mikropilota MP1 | NEW |  | 0.249 | 0.393 | 0.197 | 0.049 | 8 | 0.393 | ZELEZOBETONOVÁ KCE | MP02.02.0023 | S 355 | C 20/25 | NEMSOK - Označení: MIKROPILOTA MP1; Průměr (2): 250; Délka kořene: 8000; Druh výztuže: TR 108/10
MIKROPILOTA MP1 | Základy | PAD_FOOTING | 0886SZa0000028669 | Mikropilota MP1 | NEW |  | 0.249 | 0.393 | 0.197 | 0.049 | 8 | 0.393 | ZELEZOBETONOVÁ KCE | MP02.02.0024 | S 355 | C 20/25 | NEMSOK - Označení: MIKROPILOTA MP1; Průměr (2): 250; Délka kořene: 8000; Druh výztuže: TR 108/10
MIKROPILOTA MP1 | Základy | PAD_FOOTING | 0886SZa0000028670 | Mikropilota MP1 | NEW |  | 0.249 | 0.393 | 0.197 | 0.049 | 8 | 0.393 | ZELEZOBETONOVÁ KCE | MP02.02.0025 | S 355 | C 20/25 | NEMSOK - Označení: MIKROPILOTA MP1; Průměr (2): 250; Délka kořene: 8000; Druh výztuže: TR 108/10
MIKROPILOTA MP1 | Základy | PAD_FOOTING | 0886SZa0000028671 | Mikropilota MP1 | NEW |  | 0.249 | 0.393 | 0.197 | 0.049 | 8 | 0.393 | ZELEZOBETONOVÁ KCE | MP02.02.0026 | S 355 | C 20/25 | NEMSOK - Označení: MIKROPILOTA MP1; Průměr (2): 250; Délka kořene: 8000; Druh výztuže: TR 108/10
MIKROPILOTA MP1 | Základy | PAD_FOOTING | 0886SZa0000028672 | Mikropilota MP1 | NEW |  | 0.249 | 0.393 | 0.197 | 0.049 | 8 | 0.393 | ZELEZOBETONOVÁ KCE | MP02.02.0027 | S 355 | C 20/25 | NEMSOK - Označení: MIKROPILOTA MP1; Průměr (2): 250; Délka kořene: 8000; Druh výztuže: TR 108/10
MIKROPILOTA MP1 | Základy | PAD_FOOTING | 0886SZa0000028673 | Mikropilota MP1 | NEW |  | 0.249 | 0.393 | 0.197 | 0.049 | 8 | 0.393 | ZELEZOBETONOVÁ KCE | MP02.02.0028 | S 355 | C 20/25 | NEMSOK - Označení: MIKROPILOTA MP1; Průměr (2): 250; Délka kořene: 8000; Druh výztuže: TR 108/10
MIKROPILOTA MP1 | Základy | PAD_FOOTING | 0886SZa0000028674 | Mikropilota MP1 | NEW |  | 0.249 | 0.393 | 0.197 | 0.049 | 8 | 0.393 | ZELEZOBETONOVÁ KCE | MP02.02.0029 | S 355 | C 20/25 | NEMSOK - Označení: MIKROPILOTA MP1; Průměr (2): 250; Délka kořene: 8000; Druh výztuže: TR 108/10
MIKROPILOTA MP1 | Základy | PAD_FOOTING | 0886SZa0000028675 | Mikropilota MP1 | NEW |  | 0.249 | 0.393 | 0.197 | 0.049 | 8 | 0.393 | ZELEZOBETONOVÁ KCE | MP02.02.0030 | S 355 | C 20/25 | NEMSOK - Označení: MIKROPILOTA MP1; Průměr (2): 250; Délka kořene: 8000; Druh výztuže: TR 108/10
MIKROPILOTA MP1 | Základy | PAD_FOOTING | 0886SZa0000028676 | Mikropilota MP1 | NEW |  | 0.249 | 0.393 | 0.197 | 0.049 | 8 | 0.393 | ZELEZOBETONOVÁ KCE | MP02.02.0031 | S 355 | C 20/25 | NEMSOK - Označení: MIKROPILOTA MP1; Průměr (2): 250; Délka kořene: 8000; Druh výztuže: TR 108/10
MIKROPILOTA MP1 | Základy | PAD_FOOTING | 0886SZa0000028677 | Mikropilota MP1 | NEW |  | 0.249 | 0.393 | 0.197 | 0.049 | 8 | 0.393 | ZELEZOBETONOVÁ KCE | MP02.02.0032 | S 355 | C 20/25 | NEMSOK - Označení: MIKROPILOTA MP1; Průměr (2): 250; Délka kořene: 8000; Druh výztuže: TR 108/10
MIKROPILOTA MP1 | Základy | PAD_FOOTING | 0886SZa0000028678 | Mikropilota MP1 | NEW |  | 0.249 | 0.393 | 0.197 | 0.049 | 8 | 0.393 | ZELEZOBETONOVÁ KCE | MP02.02.0033 | S 355 | C 20/25 | NEMSOK - Označení: MIKROPILOTA MP1; Průměr (2): 250; Délka kořene: 8000; Druh výztuže: TR 108/10
MIKROPILOTA MP1 | Základy | PAD_FOOTING | 0886SZa0000028679 | Mikropilota MP1 | NEW |  | 0.249 | 0.393 | 0.197 | 0.049 | 8 | 0.393 | ZELEZOBETONOVÁ KCE | MP02.02.0034 | S 355 | C 20/25 | NEMSOK - Označení: MIKROPILOTA MP1; Průměr (2): 250; Délka kořene: 8000; Druh výztuže: TR 108/10
MIKROPILOTA MP1 | Základy | PAD_FOOTING | 0886SZa0000028680 | Mikropilota MP1 | NEW |  | 0.249 | 0.393 | 0.197 | 0.049 | 8 | 0.393 | ZELEZOBETONOVÁ KCE | MP02.02.0035 | S 355 | C 20/25 | NEMSOK - Označení: MIKROPILOTA MP1; Průměr (2): 250; Délka kořene: 8000; Druh výztuže: TR 108/10
MIKROPILOTA MP1 | Základy | PAD_FOOTING | 0886SZa0000028681 | Mikropilota MP1 | NEW |  | 0.249 | 0.393 | 0.197 | 0.049 | 8 | 0.393 | ZELEZOBETONOVÁ KCE | MP02.02.0036 | S 355 | C 20/25 | NEMSOK - Označení: MIKROPILOTA MP1; Průměr (2): 250; Délka kořene: 8000; Druh výztuže: TR 108/10
MIKROPILOTA MP1 | Základy | PAD_FOOTING | 0886SZa0000028682 | Mikropilota MP1 | NEW |  | 0.249 | 0.393 | 0.197 | 0.049 | 8 | 0.393 | ZELEZOBETONOVÁ KCE | MP02.02.0037 | S 355 | C 20/25 | NEMSOK - Označení: MIKROPILOTA MP1; Průměr (2): 250; Délka kořene: 8000; Druh výztuže: TR 108/10
MIKROPILOTA MP1 | Základy | PAD_FOOTING | 0886SZa0000028683 | Mikropilota MP1 | NEW |  | 0.249 | 0.393 | 0.197 | 0.049 | 8 | 0.393 | ZELEZOBETONOVÁ KCE | MP02.02.0038 | S 355 | C 20/25 | NEMSOK - Označení: MIKROPILOTA MP1; Průměr (2): 250; Délka kořene: 8000; Druh výztuže: TR 108/10
MIKROPILOTA MP1 | Základy | PAD_FOOTING | 0886SZa0000028684 | Mikropilota MP1 | NEW |  | 0.249 | 0.393 | 0.197 | 0.049 | 8 | 0.393 | ZELEZOBETONOVÁ KCE | MP02.02.0039 | S 355 | C 20/25 | NEMSOK - Označení: MIKROPILOTA MP1; Průměr (2): 250; Délka kořene: 8000; Druh výztuže: TR 108/10
MIKROPILOTA MP1 | Základy | PAD_FOOTING | 0886SZa0000028685 | Mikropilota MP1 | NEW |  | 0.249 | 0.393 | 0.197 | 0.049 | 8 | 0.393 | ZELEZOBETONOVÁ KCE | MP02.02.0040 | S 355 | C 20/25 | NEMSOK - Označení: MIKROPILOTA MP1; Průměr (2): 250; Délka kořene: 8000; Druh výztuže: TR 108/10
MIKROPILOTA MP1 | Základy | PAD_FOOTING | 0886SZa0000028686 | Mikropilota MP1 | NEW |  | 0.249 | 0.393 | 0.197 | 0.049 | 8 | 0.393 | ZELEZOBETONOVÁ KCE | MP02.02.0041 | S 355 | C 20/25 | NEMSOK - Označení: MIKROPILOTA MP1; Průměr (2): 250; Délka kořene: 8000; Druh výztuže: TR 108/10
MIKROPILOTA MP1 | Základy | PAD_FOOTING | 0886SZa0000028687 | Mikropilota MP1 | NEW |  | 0.249 | 0.393 | 0.197 | 0.049 | 8 | 0.393 | ZELEZOBETONOVÁ KCE | MP02.02.0042 | S 355 | C 20/25 | NEMSOK - Označení: MIKROPILOTA MP1; Průměr (2): 250; Délka kořene: 8000; Druh výztuže: TR 108/10
MIKROPILOTA MP1 | Základy | PAD_FOOTING | 0886SZa0000028688 | Mikropilota MP1 | NEW |  | 0.249 | 0.393 | 0.197 | 0.049 | 8 | 0.393 | ZELEZOBETONOVÁ KCE | MP02.02.0043 | S 355 | C 20/25 | NEMSOK - Označení: MIKROPILOTA MP1; Průměr (2): 250; Délka kořene: 8000; Druh výztuže: TR 108/10
MIKROPILOTA MP1 | Základy | PAD_FOOTING | 0886SZa0000028689 | Mikropilota MP1 | NEW |  | 0.249 | 0.393 | 0.197 | 0.049 | 8 | 0.393 | ZELEZOBETONOVÁ KCE | MP02.02.0044 | S 355 | C 20/25 | NEMSOK - Označení: MIKROPILOTA MP1; Průměr (2): 250; Délka kořene: 8000; Druh výztuže: TR 108/10
MIKROPILOTA MP1 | Základy | PAD_FOOTING | 0886SZa0000028690 | Mikropilota MP1 | NEW |  | 0.249 | 0.393 | 0.197 | 0.049 | 8 | 0.393 | ZELEZOBETONOVÁ KCE | MP02.02.0045 | S 355 | C 20/25 | NEMSOK - Označení: MIKROPILOTA MP1; Průměr (2): 250; Délka kořene: 8000; Druh výztuže: TR 108/10
MIKROPILOTA MP1 | Základy | PAD_FOOTING | 0886SZa0000028691 | Mikropilota MP1 | NEW |  | 0.249 | 0.393 | 0.197 | 0.049 | 8 | 0.393 | ZELEZOBETONOVÁ KCE | MP02.02.0046 | S 355 | C 20/25 | NEMSOK - Označení: MIKROPILOTA MP1; Průměr (2): 250; Délka kořene: 8000; Druh výztuže: TR 108/10
MIKROPILOTA MP1 | Základy | PAD_FOOTING | 0886SZa0000028692 | Mikropilota MP1 | NEW |  | 0.249 | 0.393 | 0.197 | 0.049 | 8 | 0.393 | ZELEZOBETONOVÁ KCE | MP02.02.0047 | S 355 | C 20/25 | NEMSOK - Označení: MIKROPILOTA MP1; Průměr (2): 250; Délka kořene: 8000; Druh výztuže: TR 108/10
MIKROPILOTA MP1 | Základy | PAD_FOOTING | 0886SZa0000028693 | Mikropilota MP1 | NEW |  | 0.249 | 0.393 | 0.197 | 0.049 | 8 | 0.393 | ZELEZOBETONOVÁ KCE | MP02.02.0048 | S 355 | C 20/25 | NEMSOK - Označení: MIKROPILOTA MP1; Průměr (2): 250; Délka kořene: 8000; Druh výztuže: TR 108/10
MIKROPILOTA MP1 | Základy | PAD_FOOTING | 0886SZa0000028694 | Mikropilota MP1 | NEW |  | 0.249 | 0.393 | 0.197 | 0.049 | 8 | 0.393 | ZELEZOBETONOVÁ KCE | MP02.02.0049 | S 355 | C 20/25 | NEMSOK - Označení: MIKROPILOTA MP1; Průměr (2): 250; Délka kořene: 8000; Druh výztuže: TR 108/10
MIKROPILOTA MP1 | Základy | PAD_FOOTING | 0886SZa0000028695 | Mikropilota MP1 | NEW |  | 0.249 | 0.393 | 0.197 | 0.049 | 8 | 0.393 | ZELEZOBETONOVÁ KCE | MP02.02.0050 | S 355 | C 20/25 | NEMSOK - Označení: MIKROPILOTA MP1; Průměr (2): 250; Délka kořene: 8000; Druh výztuže: TR 108/10
MIKROPILOTA MP1 | Základy | PAD_FOOTING | 0886SZa0000028696 | Mikropilota MP1 | NEW |  | 0.249 | 0.393 | 0.197 | 0.049 | 8 | 0.393 | ZELEZOBETONOVÁ KCE | MP02.02.0051 | S 355 | C 20/25 | NEMSOK - Označení: MIKROPILOTA MP1; Průměr (2): 250; Délka kořene: 8000; Druh výztuže: TR 108/10
MIKROPILOTA MP1 | Základy | PAD_FOOTING | 0886SZa0000028697 | Mikropilota MP1 | NEW |  | 0.249 | 0.393 | 0.197 | 0.049 | 8 | 0.393 | ZELEZOBETONOVÁ KCE | MP02.02.0052 | S 355 | C 20/25 | NEMSOK - Označení: MIKROPILOTA MP1; Průměr (2): 250; Délka kořene: 8000; Druh výztuže: TR 108/10
MIKROPILOTA MP1 | Základy | PAD_FOOTING | 0886SZa0000028698 | Mikropilota MP1 | NEW |  | 0.249 | 0.393 | 0.197 | 0.049 | 8 | 0.393 | ZELEZOBETONOVÁ KCE | MP02.02.0053 | S 355 | C 20/25 | NEMSOK - Označení: MIKROPILOTA MP1; Průměr (2): 250; Délka kořene: 8000; Druh výztuže: TR 108/10
MIKROPILOTA MP1 | Základy | PAD_FOOTING | 0886SZa0000028699 | Mikropilota MP1 | NEW |  | 0.249 | 0.393 | 0.197 | 0.049 | 8 | 0.393 | ZELEZOBETONOVÁ KCE | MP02.02.0054 | S 355 | C 20/25 | NEMSOK - Označení: MIKROPILOTA MP1; Průměr (2): 250; Délka kořene: 8000; Druh výztuže: TR 108/10
MIKROPILOTA MP1 | Základy | PAD_FOOTING | 0886SZa0000028700 | Mikropilota MP1 | NEW |  | 0.249 | 0.393 | 0.197 | 0.049 | 8 | 0.393 | ZELEZOBETONOVÁ KCE | MP02.02.0055 | S 355 | C 20/25 | NEMSOK - Označení: MIKROPILOTA MP1; Průměr (2): 250; Délka kořene: 8000; Druh výztuže: TR 108/10
MIKROPILOTA MP1 | Základy | PAD_FOOTING | 0886SZa0000028701 | Mikropilota MP1 | NEW |  | 0.249 | 0.393 | 0.197 | 0.049 | 8 | 0.393 | ZELEZOBETONOVÁ KCE | MP02.02.0056 | S 355 | C 20/25 | NEMSOK - Označení: MIKROPILOTA MP1; Průměr (2): 250; Délka kořene: 8000; Druh výztuže: TR 108/10
MIKROPILOTA MP1 | Základy | PAD_FOOTING | 0886SZa0000028702 | Mikropilota MP1 | NEW |  | 0.249 | 0.393 | 0.197 | 0.049 | 8 | 0.393 | ZELEZOBETONOVÁ KCE | MP02.02.0057 | S 355 | C 20/25 | NEMSOK - Označení: MIKROPILOTA MP1; Průměr (2): 250; Délka kořene: 8000; Druh výztuže: TR 108/10
MIKROPILOTA MP1 | Základy | PAD_FOOTING | 0886SZa0000028703 | Mikropilota MP1 | NEW |  | 0.249 | 0.393 | 0.197 | 0.049 | 8 | 0.393 | ZELEZOBETONOVÁ KCE | MP02.02.0058 | S 355 | C 20/25 | NEMSOK - Označení: MIKROPILOTA MP1; Průměr (2): 250; Délka kořene: 8000; Druh výztuže: TR 108/10
MIKROPILOTA MP1 | Základy | PAD_FOOTING | 0886SZa0000028704 | Mikropilota MP1 | NEW |  | 0.249 | 0.393 | 0.197 | 0.049 | 8 | 0.393 | ZELEZOBETONOVÁ KCE | MP02.02.0059 | S 355 | C 20/25 | NEMSOK - Označení: MIKROPILOTA MP1; Průměr (2): 250; Délka kořene: 8000; Druh výztuže: TR 108/10
MIKROPILOTA MP1 | Základy | PAD_FOOTING | 0886SZa0000028705 | Mikropilota MP1 | NEW |  | 0.249 | 0.393 | 0.197 | 0.049 | 8 | 0.393 | ZELEZOBETONOVÁ KCE | MP02.02.0060 | S 355 | C 20/25 | NEMSOK - Označení: MIKROPILOTA MP1; Průměr (2): 250; Délka kořene: 8000; Druh výztuže: TR 108/10
MIKROPILOTA MP1 | Základy | PAD_FOOTING | 0886SZa0000028706 | Mikropilota MP1 | NEW |  | 0.249 | 0.393 | 0.197 | 0.049 | 8 | 0.393 | ZELEZOBETONOVÁ KCE | MP02.02.0061 | S 355 | C 20/25 | NEMSOK - Označení: MIKROPILOTA MP1; Průměr (2): 250; Délka kořene: 8000; Druh výztuže: TR 108/10
MIKROPILOTA MP1 | Základy | PAD_FOOTING | 0886SZa0000028707 | Mikropilota MP1 | NEW |  | 0.249 | 0.393 | 0.197 | 0.049 | 8 | 0.393 | ZELEZOBETONOVÁ KCE | MP02.02.0062 | S 355 | C 20/25 | NEMSOK - Označení: MIKROPILOTA MP1; Průměr (2): 250; Délka kořene: 8000; Druh výztuže: TR 108/10
MIKROPILOTA MP1 | Základy | PAD_FOOTING | 0886SZa0000028708 | Mikropilota MP1 | NEW |  | 0.249 | 0.393 | 0.197 | 0.049 | 8 | 0.393 | ZELEZOBETONOVÁ KCE | MP02.02.0063 | S 355 | C 20/25 | NEMSOK - Označení: MIKROPILOTA MP1; Průměr (2): 250; Délka kořene: 8000; Druh výztuže: TR 108/10
MIKROPILOTA MP1 | Základy | PAD_FOOTING | 0886SZa0000028709 | Mikropilota MP1 | NEW |  | 0.249 | 0.393 | 0.197 | 0.049 | 8 | 0.393 | ZELEZOBETONOVÁ KCE | MP02.02.0064 | S 355 | C 20/25 | NEMSOK - Označení: MIKROPILOTA MP1; Průměr (2): 250; Délka kořene: 8000; Druh výztuže: TR 108/10
MIKROPILOTA MP1 | Základy | PAD_FOOTING | 0886SZa0000028710 | Mikropilota MP1 | NEW |  | 0.249 | 0.393 | 0.197 | 0.049 | 8 | 0.393 | ZELEZOBETONOVÁ KCE | MP02.02.0065 | S 355 | C 20/25 | NEMSOK - Označení: MIKROPILOTA MP1; Průměr (2): 250; Délka kořene: 8000; Druh výztuže: TR 108/10
MIKROPILOTA MP1 | Základy | PAD_FOOTING | 0886SZa0000028711 | Mikropilota MP1 | NEW |  | 0.249 | 0.393 | 0.197 | 0.049 | 8 | 0.393 | ZELEZOBETONOVÁ KCE | MP02.02.0066 | S 355 | C 20/25 | NEMSOK - Označení: MIKROPILOTA MP1; Průměr (2): 250; Délka kořene: 8000; Druh výztuže: TR 108/10
MIKROPILOTA MP1 | Základy | PAD_FOOTING | 0886SZa0000028712 | Mikropilota MP1 | NEW |  | 0.249 | 0.393 | 0.197 | 0.049 | 8 | 0.393 | ZELEZOBETONOVÁ KCE | MP02.02.0067 | S 355 | C 20/25 | NEMSOK - Označení: MIKROPILOTA MP1; Průměr (2): 250; Délka kořene: 8000; Druh výztuže: TR 108/10
MIKROPILOTA MP1 | Základy | PAD_FOOTING | 0886SZa0000028713 | Mikropilota MP1 | NEW |  | 0.249 | 0.393 | 0.197 | 0.049 | 8 | 0.393 | ZELEZOBETONOVÁ KCE | MP02.02.0068 | S 355 | C 20/25 | NEMSOK - Označení: MIKROPILOTA MP1; Průměr (2): 250; Délka kořene: 8000; Druh výztuže: TR 108/10
MIKROPILOTA MP1 | Základy | PAD_FOOTING | 0886SZa0000028714 | Mikropilota MP1 | NEW |  | 0.249 | 0.393 | 0.197 | 0.049 | 8 | 0.393 | ZELEZOBETONOVÁ KCE | MP02.02.0069 | S 355 | C 20/25 | NEMSOK - Označení: MIKROPILOTA MP1; Průměr (2): 250; Délka kořene: 8000; Druh výztuže: TR 108/10
MIKROPILOTA MP1 | Základy | PAD_FOOTING | 0886SZa0000028715 | Mikropilota MP1 | NEW |  | 0.249 | 0.393 | 0.197 | 0.049 | 8 | 0.393 | ZELEZOBETONOVÁ KCE | MP02.02.0070 | S 355 | C 20/25 | NEMSOK - Označení: MIKROPILOTA MP1; Průměr (2): 250; Délka kořene: 8000; Druh výztuže: TR 108/10
MIKROPILOTA MP1 | Základy | PAD_FOOTING | 0886SZa0000028716 | Mikropilota MP1 | NEW |  | 0.249 | 0.393 | 0.197 | 0.049 | 8 | 0.393 | ZELEZOBETONOVÁ KCE | MP02.02.0071 | S 355 | C 20/25 | NEMSOK - Označení: MIKROPILOTA MP1; Průměr (2): 250; Délka kořene: 8000; Druh výztuže: TR 108/10
 | Půdorys 1.PP | PAD_FOOTING | 1364SZa0798496731 | Základová patka | NEW | yes | 1.4 | 1.89 | 1.35 | 1.89 | 1 | 1.89 | ZELEZOBETONOVÁ KCE | ZP02.02.1003 | B500B | C25/30-XC2,XA1 | NEMSOK - Stupeň vyztužení: 70; Krytí výztuže: 50mm; Statická funkce: Ano
 | Půdorys 1.PP | STRIP_FOOTING | 1364ZPa0798490411 | Základový pás | NEW | yes | 0.947 | 0.473 | 0.5 | 0.473 | 1 | 0.473 | ZELEZOBETONOVÁ KCE | ZP02.02.0041 | B500B | C25/30-XC2,XA1 | NEMSOK - Stupeň vyztužení: 70; Krytí výztuže: 50mm; Statická funkce: Ano
 | Půdorys 1.PP | STRIP_FOOTING | 1364ZPa0798490415 | Základový pás | NEW | yes | 3.65 | 1.825 | 0.5 | 1.825 | 1 | 1.825 | ZELEZOBETONOVÁ KCE | ZP02.02.0040 | B500B | C25/30-XC2,XA1 | NEMSOK - Stupeň vyztužení: 70; Krytí výztuže: 50mm; Statická funkce: Ano
 | Půdorys 1.PP | STRIP_FOOTING | 1364ZPa0798490437 | Základový pás | NEW | yes | 6.895 | 3.441 | 0.5 | 3.447 | 1 | 3.447 | ZELEZOBETONOVÁ KCE | ZP02.02.0039 | B500B | C25/30-XC2,XA1 | NEMSOK - Stupeň vyztužení: 70; Krytí výztuže: 50mm; Statická funkce: Ano
 | Půdorys 1.PP | STRIP_FOOTING | 1364ZPa0798490464 | Základový pás | NEW | yes | 3.755 | 1.878 | 0.5 | 1.877 | 1 | 1.878 | ZELEZOBETONOVÁ KCE | ZP02.02.0038 | B500B | C25/30-XC2,XA1 | NEMSOK - Stupeň vyztužení: 70; Krytí výztuže: 50mm; Statická funkce: Ano
 | Půdorys 1.PP | STRIP_FOOTING | 1364ZPa0798490468 | Základový pás | NEW | yes | 1.3 | 0.65 | 0.5 | 0.65 | 1 | 0.65 | ZELEZOBETONOVÁ KCE | ZP02.02.0037 | B500B | C25/30-XC2,XA1 | NEMSOK - Stupeň vyztužení: 70; Krytí výztuže: 50mm; Statická funkce: Ano
 | Půdorys 1.PP | STRIP_FOOTING | 1364ZPa0798490478 | Základový pás | NEW | yes | 3.645 | 1.823 | 0.5 | 1.822 | 1 | 1.823 | ZELEZOBETONOVÁ KCE | ZP02.02.0036 | B500B | C25/30-XC2,XA1 | NEMSOK - Stupeň vyztužení: 70; Krytí výztuže: 50mm; Statická funkce: Ano
 | Půdorys 1.PP | STRIP_FOOTING | 1364ZPa0798490490 | Základový pás | NEW | yes | 9.645 | 4.807 | 0.5 | 4.823 | 1 | 4.823 | ZELEZOBETONOVÁ KCE | ZP02.02.0035 | B500B | C25/30-XC2,XA1 | NEMSOK - Stupeň vyztužení: 70; Krytí výztuže: 50mm; Statická funkce: Ano
 | Půdorys 1.PP | STRIP_FOOTING | 1364ZPa0798490502 | Základový pás | NEW | yes | 3.845 | 1.923 | 0.5 | 1.922 | 1 | 1.923 | ZELEZOBETONOVÁ KCE | ZP02.02.0034 | B500B | C25/30-XC2,XA1 | NEMSOK - Stupeň vyztužení: 70; Krytí výztuže: 50mm; Statická funkce: Ano
 | Půdorys 1.PP | STRIP_FOOTING | 1364ZPa0798490526 | Základový pás | NEW | yes | 10.25 | 5.109 | 0.5 | 5.125 | 1 | 5.125 | ZELEZOBETONOVÁ KCE | ZP02.02.0033 | B500B | C25/30-XC2,XA1 | NEMSOK - Stupeň vyztužení: 70; Krytí výztuže: 50mm; Statická funkce: Ano
 | Půdorys 1.PP | STRIP_FOOTING | 1364ZPa0798490538 | Základový pás | NEW | yes | 2.695 | 1.3 | 0.5 | 1.348 | 1 | 1.348 | ZELEZOBETONOVÁ KCE | ZP02.02.0032 | B500B | C25/30-XC2,XA1 | NEMSOK - Stupeň vyztužení: 70; Krytí výztuže: 50mm; Statická funkce: Ano
 | Půdorys 1.PP | STRIP_FOOTING | 1364ZPa0798490601 | Základový pás | NEW | yes | 0.955 | 0.477 | 0.5 | 0.477 | 1 | 0.477 | ZELEZOBETONOVÁ KCE | ZP02.02.0031 | B500B | C25/30-XC2,XA1 | NEMSOK - Stupeň vyztužení: 70; Krytí výztuže: 50mm; Statická funkce: Ano
 | Půdorys 1.PP | STRIP_FOOTING | 1364ZPa0798490637 | Základový pás | NEW | yes | 0.986 | 0.486 | 0.5 | 0.493 | 1 | 0.493 | ZELEZOBETONOVÁ KCE | ZP02.02.0030 | B500B | C25/30-XC2,XA1 | NEMSOK - Stupeň vyztužení: 70; Krytí výztuže: 50mm; Statická funkce: Ano
 | Půdorys 1.PP | STRIP_FOOTING | 1364ZPa0798490656 | Základový pás | NEW | yes | 7.642 | 3.783 | 0.5 | 3.821 | 1 | 3.821 | ZELEZOBETONOVÁ KCE | ZP02.02.0029 | B500B | C25/30-XC2,XA1 | NEMSOK - Stupeň vyztužení: 70; Krytí výztuže: 50mm; Statická funkce: Ano
 | Půdorys 1.PP | STRIP_FOOTING | 1364ZPa0798490677 | Základový pás | NEW | yes | 3.213 | 0.482 | 0.5 | 1.606 | 0.3 | 0.482 | ZELEZOBETONOVÁ KCE | ZP02.02.0028 | B500B | C25/30-XC2,XA1 | NEMSOK - Stupeň vyztužení: 70; Krytí výztuže: 50mm; Statická funkce: Ano
 | Půdorys 1.PP | STRIP_FOOTING | 1364ZPa0798490742 | Základový pás | NEW | yes | 3.213 | 0.482 | 0.5 | 1.606 | 0.3 | 0.482 | ZELEZOBETONOVÁ KCE | ZP02.02.0027 | B500B | C25/30-XC2,XA1 | NEMSOK - Stupeň vyztužení: 70; Krytí výztuže: 50mm; Statická funkce: Ano
 | Půdorys 1.PP | STRIP_FOOTING | 1364ZPa0798495189 | Základový pás | NEW | yes | 1.145 | 0.572 | 0.5 | 0.572 | 1 | 0.572 | ZELEZOBETONOVÁ KCE | ZP02.02.0026 | B500B | C25/30-XC2,XA1 | NEMSOK - Stupeň vyztužení: 70; Krytí výztuže: 50mm; Statická funkce: Ano
 | Půdorys 1.PP | STRIP_FOOTING | 1364ZPa0798495191 | Základový pás | NEW | yes | 0.945 | 0.473 | 0.5 | 0.473 | 1 | 0.473 | ZELEZOBETONOVÁ KCE | ZP02.02.0025 | B500B | C25/30-XC2,XA1 | NEMSOK - Stupeň vyztužení: 70; Krytí výztuže: 50mm; Statická funkce: Ano
 | Půdorys 1.PP | STRIP_FOOTING | 1364ZPa0798495193 | Základový pás | NEW | yes | 1 | 0.5 | 0.5 | 0.5 | 1 | 0.5 | ZELEZOBETONOVÁ KCE | ZP02.02.0024 | B500B | C25/30-XC2,XA1 | NEMSOK - Stupeň vyztužení: 70; Krytí výztuže: 50mm; Statická funkce: Ano
 | Půdorys 1.PP | STRIP_FOOTING | 1364ZPa0798495195 | Základový pás | NEW | yes | 2.98 | 1.49 | 0.5 | 1.49 | 1 | 1.49 | ZELEZOBETONOVÁ KCE | ZP02.02.0023 | B500B | C25/30-XC2,XA1 | NEMSOK - Stupeň vyztužení: 70; Krytí výztuže: 50mm; Statická funkce: Ano
 | Půdorys 1.PP | STRIP_FOOTING | 1364ZPa0798495197 | Základový pás | NEW | yes | 3.095 | 1.547 | 0.5 | 1.548 | 1 | 1.547 | ZELEZOBETONOVÁ KCE | ZP02.02.0022 | B500B | C25/30-XC2,XA1 | NEMSOK - Stupeň vyztužení: 70; Krytí výztuže: 50mm; Statická funkce: Ano
 | Půdorys 1.PP | STRIP_FOOTING | 1364ZPa0798495199 | Základový pás | NEW | yes | 3.6 | 1.8 | 0.5 | 1.8 | 1 | 1.8 | ZELEZOBETONOVÁ KCE | ZP02.02.0021 | B500B | C25/30-XC2,XA1 | NEMSOK - Stupeň vyztužení: 70; Krytí výztuže: 50mm; Statická funkce: Ano
 | Půdorys 1.PP | STRIP_FOOTING | 1364ZPa0798495201 | Základový pás | NEW | yes | 3.125 | 1.547 | 0.5 | 1.563 | 1 | 1.563 | ZELEZOBETONOVÁ KCE | ZP02.02.0020 | B500B | C25/30-XC2,XA1 | NEMSOK - Stupeň vyztužení: 70; Krytí výztuže: 50mm; Statická funkce: Ano
 | Půdorys 1.PP | STRIP_FOOTING | 1364ZPa0798495203 | Základový pás | NEW | yes | 0.875 | 0.437 | 0.5 | 0.437 | 1 | 0.437 | ZELEZOBETONOVÁ KCE | ZP02.02.0019 | B500B | C25/30-XC2,XA1 | NEMSOK - Stupeň vyztužení: 70; Krytí výztuže: 50mm; Statická funkce: Ano
 | Půdorys 1.PP | STRIP_FOOTING | 1364ZPa0798495205 | Základový pás | NEW | yes | 14.719 | 7.359 | 0.5 | 7.359 | 1 | 7.359 | ZELEZOBETONOVÁ KCE | ZP02.02.0018 | B500B | C25/30-XC2,XA1 | NEMSOK - Stupeň vyztužení: 70; Krytí výztuže: 50mm; Statická funkce: Ano
 | Půdorys 1.PP | STRIP_FOOTING | 1364ZPa0798495208 | Základový pás | NEW | yes | 4.175 | 2.056 | 0.5 | 2.088 | 1 | 2.088 | ZELEZOBETONOVÁ KCE | ZP02.02.0017 | B500B | C25/30-XC2,XA1 | NEMSOK - Stupeň vyztužení: 70; Krytí výztuže: 50mm; Statická funkce: Ano
 | Půdorys 1.PP | STRIP_FOOTING | 1364ZPa0798495210 | Základový pás | NEW | yes | 2.27 | 1.135 | 0.5 | 1.135 | 1 | 1.135 | ZELEZOBETONOVÁ KCE | ZP02.02.0016 | B500B | C25/30-XC2,XA1 | NEMSOK - Stupeň vyztužení: 70; Krytí výztuže: 50mm; Statická funkce: Ano
 | Půdorys 1.PP | STRIP_FOOTING | 1364ZPa0798495216 | Základový pás | NEW | yes | 1.28 | 0.64 | 0.5 | 0.64 | 1 | 0.64 | ZELEZOBETONOVÁ KCE | ZP02.02.0015 | B500B | C25/30-XC2,XA1 | NEMSOK - Stupeň vyztužení: 70; Krytí výztuže: 50mm; Statická funkce: Ano
 | Půdorys 1.PP | STRIP_FOOTING | 1364ZPa0798495218 | Základový pás | NEW | yes | 8.145 | 4.057 | 0.5 | 4.073 | 1 | 4.073 | ZELEZOBETONOVÁ KCE | ZP02.02.0014 | B500B | C25/30-XC2,XA1 | NEMSOK - Stupeň vyztužení: 70; Krytí výztuže: 50mm; Statická funkce: Ano
 | Půdorys 1.PP | STRIP_FOOTING | 1364ZPa0798495220 | Základový pás | NEW | yes | 0.8 | 0.4 | 0.5 | 0.4 | 1 | 0.4 | ZELEZOBETONOVÁ KCE | ZP02.02.0013 | B500B | C25/30-XC2,XA1 | NEMSOK - Stupeň vyztužení: 70; Krytí výztuže: 50mm; Statická funkce: Ano
 | Půdorys 1.PP | STRIP_FOOTING | 1364ZPa0798495222 | Základový pás | NEW | yes | 1.35 | 0.675 | 0.5 | 0.675 | 1 | 0.675 | ZELEZOBETONOVÁ KCE | ZP02.02.0012 | B500B | C25/30-XC2,XA1 | NEMSOK - Stupeň vyztužení: 70; Krytí výztuže: 50mm; Statická funkce: Ano
 | Půdorys 1.PP | STRIP_FOOTING | 1364ZPa0798495224 | Základový pás | NEW | yes | 9.58 | 4.79 | 0.5 | 4.79 | 1 | 4.79 | ZELEZOBETONOVÁ KCE | ZP02.02.0011 | B500B | C25/30-XC2,XA1 | NEMSOK - Stupeň vyztužení: 70; Krytí výztuže: 50mm; Statická funkce: Ano
 | Půdorys 1.PP | STRIP_FOOTING | 1364ZPa0798495232 | Základový pás | NEW | yes | 5.775 | 2.887 | 0.5 | 2.887 | 1 | 2.887 | ZELEZOBETONOVÁ KCE | ZP02.02.0010 | B500B | C25/30-XC2,XA1 | NEMSOK - Stupeň vyztužení: 70; Krytí výztuže: 50mm; Statická funkce: Ano
 | Půdorys 1.PP | STRIP_FOOTING | 1364ZPa0798495238 | Základový pás | NEW | yes | 4.625 | 2.313 | 0.5 | 2.313 | 1 | 2.313 | ZELEZOBETONOVÁ KCE | ZP02.02.0009 | B500B | C25/30-XC2,XA1 | NEMSOK - Stupeň vyztužení: 70; Krytí výztuže: 50mm; Statická funkce: Ano
 | Půdorys 1.PP | STRIP_FOOTING | 1364ZPa0798495240 | Základový pás | NEW | yes | 4.925 | 2.438 | 0.5 | 2.463 | 1 | 2.463 | ZELEZOBETONOVÁ KCE | ZP02.02.0008 | B500B | C25/30-XC2,XA1 | NEMSOK - Stupeň vyztužení: 70; Krytí výztuže: 50mm; Statická funkce: Ano
 | Půdorys 1.PP | STRIP_FOOTING | 1364ZPa0798495244 | Základový pás | NEW | yes | 11.175 | 5.588 | 0.5 | 5.588 | 1 | 5.588 | ZELEZOBETONOVÁ KCE | ZP02.02.0007 | B500B | C25/30-XC2,XA1 | NEMSOK - Stupeň vyztužení: 70; Krytí výztuže: 50mm; Statická funkce: Ano
 | Půdorys 1.PP | STRIP_FOOTING | 1364ZPa0798495694 | Základový pás | NEW | yes | 14.255 | 7.128 | 0.5 | 7.128 | 1 | 7.128 | ZELEZOBETONOVÁ KCE | ZP02.02.0006 | B500B | C25/30-XC2,XA1 | NEMSOK - Stupeň vyztužení: 70; Krytí výztuže: 50mm; Statická funkce: Ano
 | Půdorys 1.PP | STRIP_FOOTING | 1364ZPa0798495753 | Základový pás | NEW | yes | 14.826 | 7.413 | 0.5 | 7.413 | 1 | 7.413 | ZELEZOBETONOVÁ KCE | ZP02.02.0005 | B500B | C25/30-XC2,XA1 | NEMSOK - Stupeň vyztužení: 70; Krytí výztuže: 50mm; Statická funkce: Ano
 | Půdorys 1.PP | STRIP_FOOTING | 1364ZPa0798498345 | Základový pás | NEW | yes | 0.655 | 0.328 | 0.5 | 0.328 | 1 | 0.328 | ZELEZOBETONOVÁ KCE | ZP02.02.0004 | B500B | C25/30-XC2,XA1 | NEMSOK - Stupeň vyztužení: 70; Krytí výztuže: 50mm; Statická funkce: Ano
 | Půdorys 1.PP | STRIP_FOOTING | 1364ZPa0798500251 | Základový pás | NEW | yes | 1.145 | 0.541 | 0.5 | 0.573 | 1 | 0.573 | ZELEZOBETONOVÁ KCE | ZP02.02.0003 | B500B | C25/30-XC2,XA1 | NEMSOK - Stupeň vyztužení: 70; Krytí výztuže: 50mm; Statická funkce: Ano
 | Půdorys 1.PP | STRIP_FOOTING | 1364ZPa0798500268 | Základový pás | NEW | yes | 1.145 | 0.572 | 0.5 | 0.572 | 1 | 0.572 | ZELEZOBETONOVÁ KCE | ZP02.02.0002 | B500B | C25/30-XC2,XA1 | NEMSOK - Stupeň vyztužení: 70; Krytí výztuže: 50mm; Statická funkce: Ano
 | Půdorys 1.PP | STRIP_FOOTING | 1364ZPa0798506671 | Základový pás | NEW | yes | 0.295 | 0.147 | 0.5 | 0.147 | 1 | 0.147 | ZELEZOBETONOVÁ KCE | ZP02.02.0001 | B500B | C25/30-XC2,XA1 | NEMSOK - Stupeň vyztužení: 70; Krytí výztuže: 50mm; Statická funkce: Ano
 | Půdorys 1.PP | PAD_FOOTING | 1364SZa0798496738 | Základová patka | NEW | yes | 1.6 | 2.16 | 1.35 | 2.16 | 1 | 2.16 | ZELEZOBETONOVÁ KCE | ZP02.02.1002 | B500B | C25/30-XC2,XA1 | NEMSOK - Stupeň vyztužení: 70; Krytí výztuže: 50mm; Statická funkce: Ano
 | Půdorys 1.PP | PAD_FOOTING | 1364SZa0798496737 | Základová patka | NEW | yes | 0.8 | 1.28 | 1.6 | 1.28 | 1 | 1.28 | ZELEZOBETONOVÁ KCE | ZP02.02.1001 | B500B | C25/30-XC2,XA1 | NEMSOK - Stupeň vyztužení: 70; Krytí výztuže: 50mm; Statická funkce: Ano

# IfcOpeningElement: Opening (1638)
Name | In | Object Layer Attributes #1, Práce | Object Layer Attributes #1, Allright_Stavebni_dil_ID | Object Layer Attributes #1, Jednotka | Object Layer Attributes #1, Název_objektu | Status | Area (m2) | Depth (m) | Volume (m3) | Height (m) | Width (m)
Dveřní otvor | Půdorys 1.PP | Betonářské práce | 1302Dve0000000589 | m3 | Dveřní otvor | NEW | 3.636 | 0.125 | 0.454 | 2.02 | 1.8 | NEMSOK - Object Layer Attributes #1, Směr otevírání dveří: -
Dveřní otvor | Půdorys 1.PP | Betonářské práce | 1302Dve0798455749 | m3 | Dveřní otvor | NEW | 1.818 | 0.125 | 0.227 | 2.02 | 0.9 | NEMSOK - Object Layer Attributes #1, Směr otevírání dveří: P
Dveřní otvor | Půdorys 1.PP | Betonářské práce | 1302Dve0798455631 | m3 | Dveřní otvor | NEW | 1.818 | 0.125 | 0.227 | 2.02 | 0.9 | NEMSOK - Object Layer Attributes #1, Směr otevírání dveří: P
Dveřní otvor | Půdorys 1.PP | Betonářské práce | 1302Dve0798455610 | m3 | Dveřní otvor | NEW | 3.232 | 0.125 | 0.404 | 2.02 | 1.6 | NEMSOK - Object Layer Attributes #1, Směr otevírání dveří: -
Dveřní otvor | Půdorys 1.PP | Betonářské práce | 1302Dve0798455492 | m3 | Dveřní otvor | NEW | 3.232 | 0.125 | 0.404 | 2.02 | 1.6 | NEMSOK - Object Layer Attributes #1, Směr otevírání dveří: -
Dveřní otvor | Půdorys 1.PP | Betonářské práce | 1302Dve0798455727 | m3 | Dveřní otvor | NEW | 1.818 | 0.125 | 0.227 | 2.02 | 0.9 | NEMSOK - Object Layer Attributes #1, Směr otevírání dveří: P
Dveřní otvor | Půdorys 1.PP | Betonářské práce | 1302Dve0798455422 | m3 | Dveřní otvor | NEW | 3.434 | 0.125 | 0.429 | 2.02 | 1.7 | NEMSOK - Object Layer Attributes #1, Směr otevírání dveří: -
Dveřní otvor | Půdorys 1.PP | Betonářské práce | 1302Dve0798455771 | m3 | Dveřní otvor | NEW | 1.818 | 0.125 | 0.227 | 2.02 | 0.9 | NEMSOK - Object Layer Attributes #1, Směr otevírání dveří: P
Dveřní otvor | Půdorys 1.PP | Betonářské práce | 1302Dve0798455255 | m3 | Dveřní otvor | NEW | 3.434 | 0.125 | 0.429 | 2.02 | 1.7 | NEMSOK - Object Layer Attributes #1, Směr otevírání dveří: -
Dveřní otvor | Půdorys 1.PP | Betonářské práce | 1302Dve0798455931 | m3 | Dveřní otvor | NEW | 1.818 | 0.125 | 0.227 | 2.02 | 0.9 | NEMSOK - Object Layer Attributes #1, Směr otevírání dveří: P
Dveřní otvor | Půdorys 1.PP | Betonářské práce | 1302Dve0798455793 | m3 | Dveřní otvor | NEW | 1.818 | 0.125 | 0.227 | 2.02 | 0.9 | NEMSOK - Object Layer Attributes #1, Směr otevírání dveří: L
Dveřní otvor | Půdorys 1.PP | Betonářské práce | 1302Dve0798455184 | m3 | Dveřní otvor | NEW | 3.838 | 0.125 | 0.48 | 2.02 | 1.9 | NEMSOK - Object Layer Attributes #1, Směr otevírání dveří: -
Prostup deskou | Půdorys 1.PP | Betonářské práce | 1302DOt0798454124 | m3 | Otvor v desce | NEW | 0.585 | 0.65 | 0.117 | 0.2 | 0.9
Prostup deskou | Půdorys 1.PP | Betonářské práce | 1304DOt0000000003 | m3 | Otvor v desce | NEW | 0.54 | 0.6 | 0.108 | 0.2 | 0.9
Prostup deskou | Půdorys 1.PP | Betonářské práce | 1304DOt0000000005 | m3 | Otvor v desce | NEW | 0.585 | 0.65 | 0.117 | 0.2 | 0.9
Okenní otvor | Půdorys 1.NP | Zateplovací systémy | 1402Okn0798449427 | m3 | Okenní otvor | NEW | 3.24 | 0.37 | 0.389 | 1.8 | 1.8 | NEMSOK - Object Layer Attributes #2, Status: Nový; Object Layer Attributes #2, Práce: Zateplovací systémy; Object Layer Attributes #2, Allright_Stavebni_dil_ID: 1402Okn0798449426; Object Layer Attributes #2, Jednotka: m2; Object Layer Attributes #2, Název_objektu: Okenní otvor
Dveřní otvor | Půdorys 1.NP | Betonářské práce | 1402Dve0798452078 | m3 | Dveřní otvor | NEW | 2.424 | 0.125 | 0.303 | 2.02 | 1.2 | NEMSOK - Object Layer Attributes #1, Směr otevírání dveří: P
Dveřní otvor | Půdorys 1.NP | Betonářské práce | 1402Dve0798449478 | m3 | Dveřní otvor | NEW | 3.696 | 0.25 | 0.924 | 2.1 | 1.76 | NEMSOK - Object Layer Attributes #1, Směr otevírání dveří: -
Okenní otvor | Půdorys 1.NP | Zateplovací systémy | 1402Okn0798453314 | m2 | Okenní otvor | NEW | 3.51 | 0.1 | 0.351 | 1.95 | 1.8
Dveřní otvor | Půdorys 1.NP | Betonářské práce | 1402Dve0798453358 | m2 | Dveřní otvor | NEW | 3.52 | 0.15 | 0.528 | 2.2 | 1.6 | NEMSOK - Object Layer Attributes #1, Směr otevírání dveří: -
Dveřní otvor | Půdorys 1.NP | Betonářské práce | 1402Dve0798456870 | m2 | Dveřní otvor | NEW | 3.52 | 0.15 | 0.528 | 2.2 | 1.6 | NEMSOK - Object Layer Attributes #1, Směr otevírání dveří: -
Okenní otvor | Půdorys 1.NP | Zateplovací systémy | 1402Okn0798449149 | m3 | Okenní otvor | NEW | 3.24 | 0.37 | 0.389 | 1.8 | 1.8 | NEMSOK - Object Layer Attributes #2, Status: Nový; Object Layer Attributes #2, Práce: Zateplovací systémy; Object Layer Attributes #2, Allright_Stavebni_dil_ID: 1402Okn0798449150; Object Layer Attributes #2, Jednotka: m2; Object Layer Attributes #2, Název_objektu: Okenní otvor
Okenní otvor | Půdorys 1.NP | Zateplovací systémy | 1402Okn0798449183 | m3 | Okenní otvor | NEW | 3.24 | 0.37 | 0.389 | 1.8 | 1.8 | NEMSOK - Object Layer Attributes #2, Status: Nový; Object Layer Attributes #2, Práce: Zateplovací systémy; Object Layer Attributes #2, Allright_Stavebni_dil_ID: 1402Okn0798449182; Object Layer Attributes #2, Jednotka: m2; Object Layer Attributes #2, Název_objektu: Okenní otvor
Okenní otvor | Půdorys 1.NP | Zateplovací systémy | 1402Okn0798449215 | m3 | Okenní otvor | NEW | 3.24 | 0.37 | 0.389 | 1.8 | 1.8 | NEMSOK - Object Layer Attributes #2, Status: Nový; Object Layer Attributes #2, Práce: Zateplovací systémy; Object Layer Attributes #2, Allright_Stavebni_dil_ID: 1402Okn0798449216; Object Layer Attributes #2, Jednotka: m2; Object Layer Attributes #2, Název_objektu: Okenní otvor
Okenní otvor | Půdorys 1.NP | Zateplovací systémy | 1402Okn0798449117 | m3 | Okenní otvor | NEW | 3.24 | 0.37 | 0.389 | 1.8 | 1.8 | NEMSOK - Object Layer Attributes #2, Status: Nový; Object Layer Attributes #2, Práce: Zateplovací systémy; Object Layer Attributes #2, Allright_Stavebni_dil_ID: 1402Okn0798449116; Object Layer Attributes #2, Jednotka: m2; Object Layer Attributes #2, Název_objektu: Okenní otvor
Okenní otvor | Půdorys 1.NP | Zateplovací systémy | 1402Okn0798449083 | m3 | Okenní otvor | NEW | 3.24 | 0.37 | 0.389 | 1.8 | 1.8 | NEMSOK - Object Layer Attributes #2, Status: Nový; Object Layer Attributes #2, Práce: Zateplovací systémy; Object Layer Attributes #2, Allright_Stavebni_dil_ID: 1402Okn0798449084; Object Layer Attributes #2, Jednotka: m2; Object Layer Attributes #2, Název_objektu: Okenní otvor
Okenní otvor | Půdorys 1.NP | Zateplovací systémy | 1402Okn0798449051 | m3 | Okenní otvor | NEW | 3.24 | 0.37 | 0.389 | 1.8 | 1.8 | NEMSOK - Object Layer Attributes #2, Status: Nový; Object Layer Attributes #2, Práce: Zateplovací systémy; Object Layer Attributes #2, Allright_Stavebni_dil_ID: 1402Okn0798449050; Object Layer Attributes #2, Jednotka: m2; Object Layer Attributes #2, Název_objektu: Okenní otvor
Okenní otvor | Půdorys 1.NP | Zateplovací systémy | 1402Okn0798449017 | m3 | Okenní otvor | NEW | 3.24 | 0.37 | 0.389 | 1.8 | 1.8 | NEMSOK - Object Layer Attributes #2, Status: Nový; Object Layer Attributes #2, Práce: Zateplovací systémy; Object Layer Attributes #2, Allright_Stavebni_dil_ID: 1402Okn0798449018; Object Layer Attributes #2, Jednotka: m2; Object Layer Attributes #2, Název_objektu: Okenní otvor
Okenní otvor | Půdorys 1.NP | Zateplovací systémy | 1402Okn0798448985 | m3 | Okenní otvor | NEW | 3.24 | 0.37 | 0.389 | 1.8 | 1.8 | NEMSOK - Object Layer Attributes #2, Status: Nový; Object Layer Attributes #2, Práce: Zateplovací systémy; Object Layer Attributes #2, Allright_Stavebni_dil_ID: 1402Okn0798448984; Object Layer Attributes #2, Jednotka: m2; Object Layer Attributes #2, Název_objektu: Okenní otvor
Okenní otvor | Půdorys 1.NP | Zateplovací systémy | 1402Okn0798448949 | m3 | Okenní otvor | NEW | 3.24 | 0.37 | 0.389 | 1.8 | 1.8 | NEMSOK - Object Layer Attributes #2, Status: Nový; Object Layer Attributes #2, Práce: Zateplovací systémy; Object Layer Attributes #2, Allright_Stavebni_dil_ID: 1402Okn0798448950; Object Layer Attributes #2, Jednotka: m2; Object Layer Attributes #2, Název_objektu: Okenní otvor
Okenní otvor | Půdorys 1.NP | Zateplovací systémy | 1402Okn0798438692 | m3 | Okenní otvor | NEW | 3.24 | 0.37 | 0.389 | 1.8 | 1.8 | NEMSOK - Object Layer Attributes #2, Status: Nový; Object Layer Attributes #2, Práce: Zateplovací systémy; Object Layer Attributes #2, Allright_Stavebni_dil_ID: 1402Okn0798438691; Object Layer Attributes #2, Jednotka: m2; Object Layer Attributes #2, Název_objektu: Okenní otvor
Dveřní otvor | Půdorys 1.NP | Betonářské práce | 1402Dve0798458042 | m3 | Dveřní otvor | NEW | 3.41 | 0.2 | 0.682 | 2.2 | 1.55 | NEMSOK - Object Layer Attributes #1, Směr otevírání dveří: -
Okenní otvor | Půdorys 1.NP | Zateplovací systémy | 1402Okn0798453159 | m2 | Okenní otvor | NEW | 3.51 | 0.1 | 0.351 | 1.95 | 1.8
Okenní otvor | Půdorys 1.NP | Zateplovací systémy | 1402Okn0798452999 | m2 | Okenní otvor | NEW | 3.51 | 0.1 | 0.351 | 1.95 | 1.8
Okenní otvor | Půdorys 1.NP | Zateplovací systémy | 1402Okn0798452929 | m2 | Okenní otvor | NEW | 3.51 | 0.1 | 0.351 | 1.95 | 1.8
Okenní otvor | Půdorys 1.NP | Zateplovací systémy | 1402Okn0798453081 | m2 | Okenní otvor | NEW | 3.51 | 0.1 | 0.351 | 1.95 | 1.8
Okenní otvor | Půdorys 1.NP | Zateplovací systémy | 1402Okn0798453247 | m2 | Okenní otvor | NEW | 3.51 | 0.1 | 0.351 | 1.95 | 1.8
Okenní otvor | Půdorys 1.NP | Zateplovací systémy | 1402Okn0798453199 | m2 | Okenní otvor | NEW | 3.51 | 0.1 | 0.351 | 1.95 | 1.8
Okenní otvor | Půdorys 1.NP | Zateplovací systémy | 1402Okn0798453043 | m2 | Okenní otvor | NEW | 3.51 | 0.1 | 0.351 | 1.95 | 1.8
Okenní otvor | Půdorys 1.NP | Zateplovací systémy | 1402Okn0798452897 | m2 | Okenní otvor | NEW | 3.51 | 0.1 | 0.351 | 1.95 | 1.8
Okenní otvor | Půdorys 1.NP | Zateplovací systémy | 1402Okn0798452965 | m2 | Okenní otvor | NEW | 3.51 | 0.1 | 0.351 | 1.95 | 1.8
Okenní otvor | Půdorys 1.NP | Zateplovací systémy | 1402Okn0798453119 | m2 | Okenní otvor | NEW | 3.51 | 0.1 | 0.351 | 1.95 | 1.8
Okenní otvor | Půdorys 1.NP | Zateplovací systémy | 1402Okn0798452446 | m2 | Okenní otvor | NEW | 3.51 | 0.1 | 0.351 | 1.95 | 1.8
Okenní otvor | Půdorys 1.NP | Zateplovací systémy | 1402Okn0798452520 | m2 | Okenní otvor | NEW | 3.51 | 0.1 | 0.351 | 1.95 | 1.8
Dveřní otvor | Půdorys 1.NP | Betonářské práce | 1402Dve0798462413 | m2 | Dveřní otvor | NEW | 2.86 | 0.1 | 0.286 | 2.2 | 1.3 | NEMSOK - Object Layer Attributes #1, Směr otevírání dveří: -
Okenní otvor | Půdorys 1.NP | Zateplovací systémy | 1402Okn0798452480 | m2 | Okenní otvor | NEW | 3.51 | 0.1 | 0.351 | 1.95 | 1.8
Okenní otvor | Půdorys 1.NP | Zateplovací systémy | 1402Okn0798452562 | m2 | Okenní otvor | NEW | 3.51 | 0.1 | 0.351 | 1.95 | 1.8
Okenní otvor | Půdorys 1.NP | Zateplovací systémy | 1402Okn0798452366 | m2 | Okenní otvor | NEW | 3.51 | 0.1 | 0.351 | 1.95 | 1.8
Okenní otvor | Půdorys 1.NP | Zateplovací systémy | 1402Okn0798452239 | m2 | Okenní otvor | NEW | 3.51 | 0.1 | 0.351 | 1.95 | 1.8
Okenní otvor | Půdorys 1.NP | Zateplovací systémy | 1402Okn0798452410 | m2 | Okenní otvor | NEW | 3.51 | 0.1 | 0.351 | 1.95 | 1.8
Dveřní otvor | Půdorys 1.NP | Betonářské práce | 1402Dve0798453772 | m3 | Dveřní otvor | NEW | 1.414 | 0.125 | 0.177 | 2.02 | 0.7 | NEMSOK - Object Layer Attributes #1, Směr otevírání dveří: P
Dveřní otvor | Půdorys 1.NP | Betonářské práce | 1402Dve0798454019 | m3 | Dveřní otvor | NEW | 1.414 | 0.125 | 0.177 | 2.02 | 0.7 | NEMSOK - Object Layer Attributes #1, Směr otevírání dveří: P
Dveřní otvor | Půdorys 1.NP | Betonářské práce | 1402Dve0798454192 | m3 | Dveřní otvor | NEW | 1.414 | 0.125 | 0.177 | 2.02 | 0.7 | NEMSOK - Object Layer Attributes #1, Směr otevírání dveří: P
Dveřní otvor | Půdorys 1.NP | Betonářské práce | 1402Dve0798455039 | m3 | Dveřní otvor | NEW | 1.818 | 0.125 | 0.227 | 2.02 | 0.9 | NEMSOK - Object Layer Attributes #1, Směr otevírání dveří: P
Dveřní otvor | Půdorys 1.NP | Betonářské práce | 1402Dve0798454965 | m3 | Dveřní otvor | NEW | 1.818 | 0.125 | 0.227 | 2.02 | 0.9 | NEMSOK - Object Layer Attributes #1, Směr otevírání dveří: P
Dveřní otvor | Půdorys 1.NP | Betonářské práce | 1402Dve0798453945 | m3 | Dveřní otvor | NEW | 1.414 | 0.125 | 0.177 | 2.02 | 0.7 | NEMSOK - Object Layer Attributes #1, Směr otevírání dveří: L
Dveřní otvor | Půdorys 1.NP | Betonářské práce | 1402Dve0798455142 | m3 | Dveřní otvor | NEW | 1.818 | 0.125 | 0.227 | 2.02 | 0.9 | NEMSOK - Object Layer Attributes #1, Směr otevírání dveří: L
Dveřní otvor | Půdorys 1.NP | Betonářské práce | 1402Dve0798454076 | m3 | Dveřní otvor | NEW | 1.818 | 0.125 | 0.227 | 2.02 | 0.9 | NEMSOK - Object Layer Attributes #1, Směr otevírání dveří: L
Dveřní otvor | Půdorys 1.NP | Betonářské práce | 1402Dve0798455229 | m3 | Dveřní otvor | NEW | 1.818 | 0.125 | 0.227 | 2.02 | 0.9 | NEMSOK - Object Layer Attributes #1, Směr otevírání dveří: P
Dveřní otvor | Půdorys 1.NP | Betonářské práce | 1402Dve0798455207 | m3 | Dveřní otvor | NEW | 1.414 | 0.125 | 0.177 | 2.02 | 0.7 | NEMSOK - Object Layer Attributes #1, Směr otevírání dveří: P
Okenní otvor | Půdorys 1.NP | Zateplovací systémy | 1402Okn0798457349 | m2 | Okenní otvor | NEW | 0.75 | 0.125 | 0.094 | 1.25 | 0.6
Dveřní otvor | Půdorys 1.NP | Betonářské práce | 1402Dve0798457805 | m2 | Dveřní otvor | NEW | 1.616 | 0.1 | 0.162 | 2.02 | 0.8 | NEMSOK - Object Layer Attributes #1, Směr otevírání dveří: L
Dveřní otvor | Půdorys 1.NP | Betonářské práce | 1402Dve0798457419 | m2 | Dveřní otvor | NEW | 2.02 | 0.125 | 0.253 | 2.02 | 1 | NEMSOK - Object Layer Attributes #1, Směr otevírání dveří: L
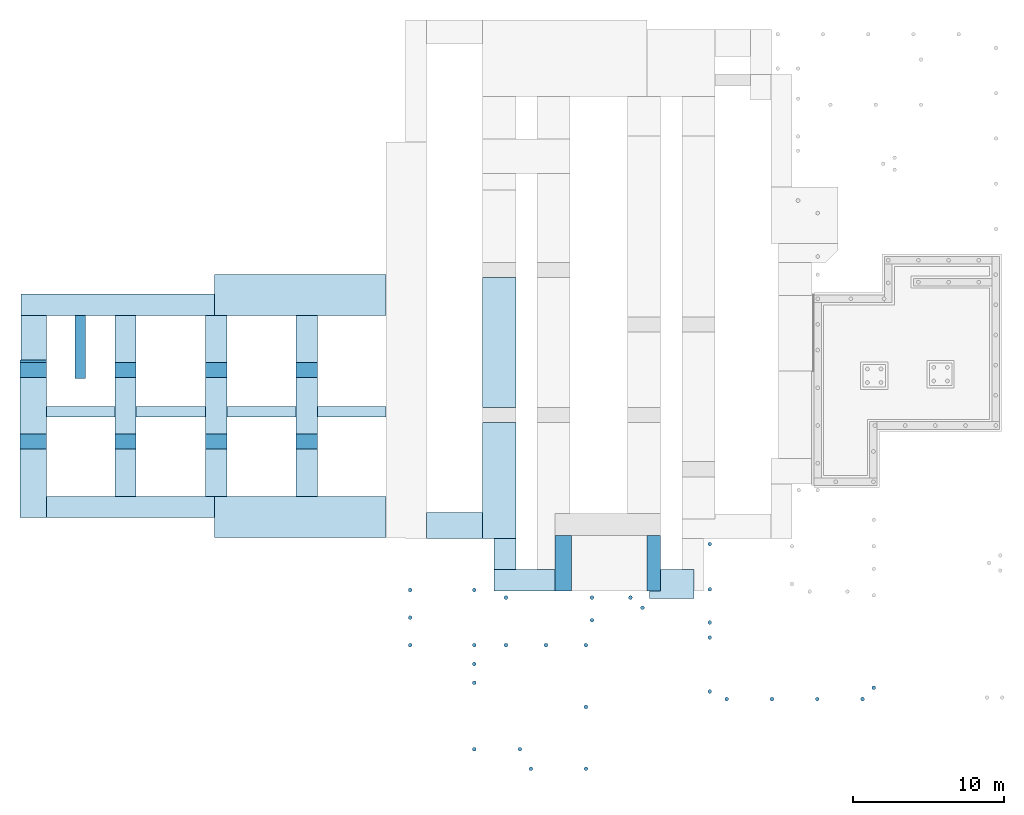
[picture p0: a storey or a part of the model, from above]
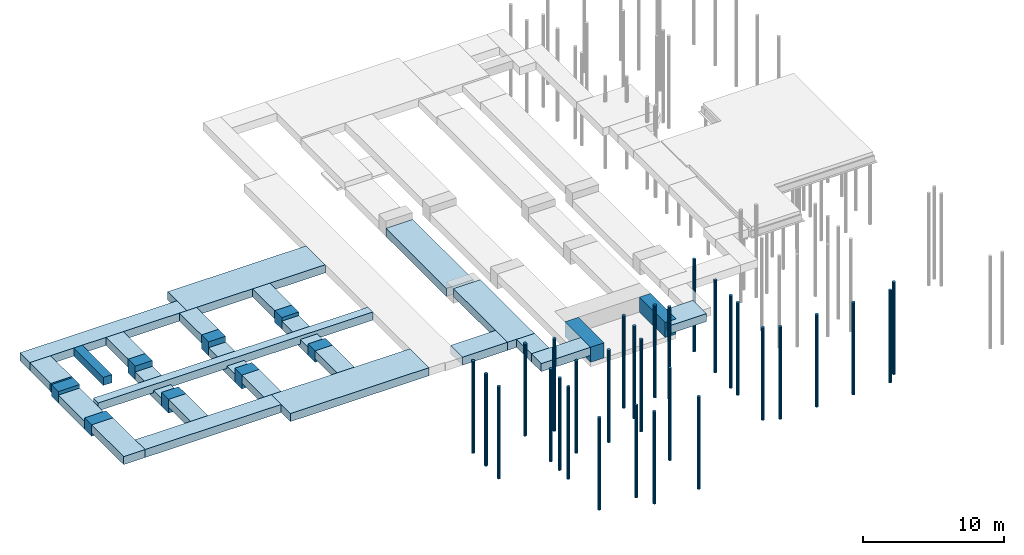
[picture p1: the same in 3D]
Properties of the parts of a building model (IFC4), part 13 of 45

# IfcOpeningElement: Opening (1638)
Name | In | Object Layer Attributes #1, Práce | Object Layer Attributes #1, Allright_Stavebni_dil_ID | Object Layer Attributes #1, Jednotka | Object Layer Attributes #1, Název_objektu | Status | Area (m2) | Depth (m) | Volume (m3) | Height (m) | Width (m)
Dveřní otvor | Půdorys 1.NP | Betonářské práce | 1402Dve0798457638 | m2 | Dveřní otvor | NEW | 1.616 | 0.125 | 0.202 | 2.02 | 0.8 | NEMSOK - Object Layer Attributes #1, Směr otevírání dveří: L
Dveřní otvor | Půdorys 1.NP | Betonářské práce | 1402Dve0798457874 | m2 | Dveřní otvor | NEW | 2.424 | 0.15 | 0.364 | 2.02 | 1.2 | NEMSOK - Object Layer Attributes #1, Směr otevírání dveří: L
Dveřní otvor | Půdorys 1.NP | Betonářské práce | 1402Dve0798458006 | m2 | Dveřní otvor | NEW | 3.41 | 0.15 | 0.512 | 2.2 | 1.55 | NEMSOK - Object Layer Attributes #1, Směr otevírání dveří: -
Dveřní otvor | Půdorys 1.NP | Betonářské práce | 1402Dve0798458017 | m2 | Dveřní otvor | NEW | 3.41 | 0.1 | 0.341 | 2.2 | 1.55 | NEMSOK - Object Layer Attributes #1, Směr otevírání dveří: P
Dveřní otvor | Půdorys 1.NP | Betonářské práce | 1402Dve0798458501 | m2 | Dveřní otvor | NEW | 3.045 | 0.05 | 0.152 | 2.1 | 1.45 | NEMSOK - Object Layer Attributes #1, Směr otevírání dveří: P
Dveřní otvor | Půdorys 1.NP | Betonářské práce | 1402Dve0798458572 | m2 | Dveřní otvor | NEW | 3.045 | 0.05 | 0.152 | 2.1 | 1.45 | NEMSOK - Object Layer Attributes #1, Směr otevírání dveří: L
Dveřní otvor | Půdorys 1.NP | Betonářské práce | 1402Dve0798463479 | m2 | Dveřní otvor | NEW | 2.424 | 0.15 | 0.364 | 2.02 | 1.2 | NEMSOK - Object Layer Attributes #1, Směr otevírání dveří: L
Dveřní otvor | Půdorys 1.NP | Betonářské práce | 1402Dve0798463501 | m2 | Dveřní otvor | NEW | 2.02 | 0.15 | 0.303 | 2.02 | 1 | NEMSOK - Object Layer Attributes #1, Směr otevírání dveří: L
Dveřní otvor | Půdorys 1.NP | Betonářské práce | 1402Dve0798459069 | m2 | Dveřní otvor | NEW | 1.616 | 0.15 | 0.242 | 2.02 | 0.8 | NEMSOK - Object Layer Attributes #1, Směr otevírání dveří: P
Dveřní otvor | Půdorys 1.NP | Betonářské práce | 1402Dve0798459010 | m2 | Dveřní otvor | NEW | 1.616 | 0.15 | 0.242 | 2.02 | 0.8 | NEMSOK - Object Layer Attributes #1, Směr otevírání dveří: L
Dveřní otvor | Půdorys 1.NP | Betonářské práce | 1402Dve0798456743 | m3 | Dveřní otvor | NEW | 2.424 | 0.125 | 0.303 | 2.02 | 1.2 | NEMSOK - Object Layer Attributes #1, Směr otevírání dveří: P
Dveřní otvor | Půdorys 1.NP | Betonářské práce | 1402Dve0798456765 | m3 | Dveřní otvor | NEW | 2.424 | 0.125 | 0.303 | 2.02 | 1.2 | NEMSOK - Object Layer Attributes #1, Směr otevírání dveří: L
Okenní otvor | Půdorys 1.NP | Zateplovací systémy | 1402Okn0798458797 | m3 | Okenní otvor | NEW | 1.08 | 0.125 | 0.135 | 1.2 | 0.9
Dveřní otvor | Půdorys 1.NP | Betonářské práce | 1402Dve0798459236 | m3 | Dveřní otvor | NEW | 5.17 | 0.125 | 0.646 | 2.2 | 2.35 | NEMSOK - Object Layer Attributes #1, Směr otevírání dveří: -
Okenní otvor | Půdorys 1.NP | Zateplovací systémy | 1402Okn0798462478 | m2 | Okenní otvor | NEW | 1.62 | 0.5 | 0.162 | 1.8 | 0.9 | NEMSOK - Object Layer Attributes #2, Status: Nový; Object Layer Attributes #2, Práce: Zateplovací systémy; Object Layer Attributes #2, Allright_Stavebni_dil_ID: 1402Okn0798462479; Object Layer Attributes #2, Jednotka: m3; Object Layer Attributes #2, Název_objektu: Okenní otvor
Okenní otvor | Půdorys 1.NP | Zateplovací systémy | 1402Okn0798462633 | m2 | Okenní otvor | NEW | 1.62 | 0.5 | 0.162 | 1.8 | 0.9 | NEMSOK - Object Layer Attributes #2, Status: Nový; Object Layer Attributes #2, Práce: Zateplovací systémy; Object Layer Attributes #2, Allright_Stavebni_dil_ID: 1402Okn0798462634; Object Layer Attributes #2, Jednotka: m3; Object Layer Attributes #2, Název_objektu: Okenní otvor
Okenní otvor | Půdorys 1.NP | Zateplovací systémy | 1402Okn0798462658 | m2 | Okenní otvor | NEW | 1.62 | 0.5 | 0.162 | 1.8 | 0.9 | NEMSOK - Object Layer Attributes #2, Status: Nový; Object Layer Attributes #2, Práce: Zateplovací systémy; Object Layer Attributes #2, Allright_Stavebni_dil_ID: 1402Okn0798462657; Object Layer Attributes #2, Jednotka: m3; Object Layer Attributes #2, Název_objektu: Okenní otvor
Okenní otvor | Půdorys 1.NP | Zateplovací systémy | 1402Okn0798462687 | m2 | Okenní otvor | NEW | 1.62 | 0.5 | 0.162 | 1.8 | 0.9 | NEMSOK - Object Layer Attributes #2, Status: Nový; Object Layer Attributes #2, Práce: Zateplovací systémy; Object Layer Attributes #2, Allright_Stavebni_dil_ID: 1402Okn0798462688; Object Layer Attributes #2, Jednotka: m3; Object Layer Attributes #2, Název_objektu: Okenní otvor
Okenní otvor | Půdorys 1.NP | Zateplovací systémy | 1402Okn0798452602 | m2 | Okenní otvor | NEW | 1.17 | 0.1 | 0.117 | 1.95 | 0.6
Okenní otvor | Půdorys 1.NP | Zateplovací systémy | 1402Okn0798438511 | m3 | Okenní otvor | NEW | 1.08 | 0.37 | 0.13 | 1.8 | 0.6 | NEMSOK - Object Layer Attributes #2, Status: Nový; Object Layer Attributes #2, Práce: Zateplovací systémy; Object Layer Attributes #2, Allright_Stavebni_dil_ID: 1402Okn0798438512; Object Layer Attributes #2, Jednotka: m2; Object Layer Attributes #2, Název_objektu: Okenní otvor
Dveřní otvor | Půdorys 1.NP | Betonářské práce | 1402Dve0798462400 | m3 | Dveřní otvor | NEW | 2.86 | 0.3 | 0.715 | 2.2 | 1.3 | NEMSOK - Object Layer Attributes #1, Směr otevírání dveří: -; Object Layer Attributes #2, Status: Nový; Object Layer Attributes #2, Práce: Betonářské práce; Object Layer Attributes #2, Allright_Stavebni_dil_ID: 1402Dve0798462399; Object Layer Attributes #2, Jednotka: m2; Object Layer Attributes #2, Název_objektu: Dveřní otvor; Object Layer Attributes #2, Směr otevírání dveří: -
Dveřní otvor | Půdorys 1.NP | Betonářské práce | 1402Dve0798462264 | m3 | Dveřní otvor | NEW | 3.52 | 0.3 | 1.056 | 2.2 | 1.6 | NEMSOK - Object Layer Attributes #1, Směr otevírání dveří: -
Dveřní otvor | Půdorys 1.NP | Betonářské práce | 1402Dve0798463284 | m3 | Dveřní otvor | NEW | 1.818 | 0.125 | 0.227 | 2.02 | 0.9 | NEMSOK - Object Layer Attributes #1, Směr otevírání dveří: P
Dveřní otvor | Půdorys 1.NP | Betonářské práce | 1402Dve0798463306 | m3 | Dveřní otvor | NEW | 1.818 | 0.125 | 0.227 | 2.02 | 0.9 | NEMSOK - Object Layer Attributes #1, Směr otevírání dveří: L
Dveřní otvor | Půdorys 1.NP | Betonářské práce | 1402Dve0798463560 | m2 | Dveřní otvor | NEW | 2.02 | 0.125 | 0.252 | 2.02 | 1 | NEMSOK - Object Layer Attributes #1, Směr otevírání dveří: P
Dveřní otvor | Půdorys 1.NP | Betonářské práce | 1402Dve0798463734 | m3 | Dveřní otvor | NEW | 1.818 | 0.125 | 0.227 | 2.02 | 0.9 | NEMSOK - Object Layer Attributes #1, Směr otevírání dveří: P
Dveřní otvor | Půdorys 1.NP | Betonářské práce | 1402Dve0798463692 | m3 | Dveřní otvor | NEW | 1.414 | 0.125 | 0.177 | 2.02 | 0.7 | NEMSOK - Object Layer Attributes #1, Směr otevírání dveří: P
Dveřní otvor | Půdorys 1.NP | Betonářské práce | 1402Dve0798463689 | m3 | Dveřní otvor | NEW | 1.414 | 0.125 | 0.177 | 2.02 | 0.7 | NEMSOK - Object Layer Attributes #1, Směr otevírání dveří: P
Dveřní otvor | Půdorys 1.NP | Betonářské práce | 1402Dve0798464106 | m3 | Dveřní otvor | NEW | 1.818 | 0.125 | 0.227 | 2.02 | 0.9 | NEMSOK - Object Layer Attributes #1, Směr otevírání dveří: L
Dveřní otvor | Půdorys 1.NP | Betonářské práce | 1402Dve0798463804 | m3 | Dveřní otvor | NEW | 1.414 | 0.125 | 0.177 | 2.02 | 0.7 | NEMSOK - Object Layer Attributes #1, Směr otevírání dveří: P
Dveřní otvor | Půdorys 1.NP | Betonářské práce | 1402Dve0798463807 | m3 | Dveřní otvor | NEW | 1.818 | 0.125 | 0.227 | 2.02 | 0.9 | NEMSOK - Object Layer Attributes #1, Směr otevírání dveří: P
Dveřní otvor | Půdorys 1.NP | Betonářské práce | 1402Dve0798463810 | m3 | Dveřní otvor | NEW | 1.414 | 0.125 | 0.177 | 2.02 | 0.7 | NEMSOK - Object Layer Attributes #1, Směr otevírání dveří: P
Dveřní otvor | Půdorys 1.NP | Betonářské práce | 1402Dve0798463801 | m3 | Dveřní otvor | NEW | 1.414 | 0.125 | 0.177 | 2.02 | 0.7 | NEMSOK - Object Layer Attributes #1, Směr otevírání dveří: P
Dveřní otvor | Půdorys 1.NP | Betonářské práce | 1402Dve0798463798 | m3 | Dveřní otvor | NEW | 1.414 | 0.125 | 0.177 | 2.02 | 0.7 | NEMSOK - Object Layer Attributes #1, Směr otevírání dveří: P
Dveřní otvor | Půdorys 1.NP | Betonářské práce | 1402Dve0798464022 | m3 | Dveřní otvor | NEW | 1.414 | 0.125 | 0.177 | 2.02 | 0.7 | NEMSOK - Object Layer Attributes #1, Směr otevírání dveří: L
Dveřní otvor | Půdorys 1.NP | Betonářské práce | 1402Dve0798455090 | m3 | Dveřní otvor | NEW | 1.818 | 0.125 | 0.227 | 2.02 | 0.9 | NEMSOK - Object Layer Attributes #1, Směr otevírání dveří: P
Okenní otvor | Půdorys 1.NP | Zateplovací systémy | 1402Okn0798467396 | m3 | Okenní otvor | NEW | 3.24 | 0.25 | 0.81 | 1.8 | 1.8
Okenní otvor | Půdorys 1.NP | Zateplovací systémy | 1402Okn0798460820 | m3 | Okenní otvor | NEW | 3.24 | 0.37 | 0.389 | 1.8 | 1.8 | NEMSOK - Object Layer Attributes #2, Status: Nový; Object Layer Attributes #2, Práce: Zateplovací systémy; Object Layer Attributes #2, Allright_Stavebni_dil_ID: 1402Okn0798460852; Object Layer Attributes #2, Jednotka: m2; Object Layer Attributes #2, Název_objektu: Okenní otvor
Okenní otvor | Půdorys 1.NP | Zateplovací systémy | 1402Okn0798460821 | m3 | Okenní otvor | NEW | 3.24 | 0.37 | 0.389 | 1.8 | 1.8 | NEMSOK - Object Layer Attributes #2, Status: Nový; Object Layer Attributes #2, Práce: Zateplovací systémy; Object Layer Attributes #2, Allright_Stavebni_dil_ID: 1402Okn0798460853; Object Layer Attributes #2, Jednotka: m2; Object Layer Attributes #2, Název_objektu: Okenní otvor
Okenní otvor | Půdorys 1.NP | Zateplovací systémy | 1402Okn0798460822 | m3 | Okenní otvor | NEW | 3.24 | 0.37 | 0.389 | 1.8 | 1.8 | NEMSOK - Object Layer Attributes #2, Status: Nový; Object Layer Attributes #2, Práce: Zateplovací systémy; Object Layer Attributes #2, Allright_Stavebni_dil_ID: 1402Okn0798460854; Object Layer Attributes #2, Jednotka: m2; Object Layer Attributes #2, Název_objektu: Okenní otvor
Okenní otvor | Půdorys 1.NP | Zateplovací systémy | 1402Okn0798460823 | m3 | Okenní otvor | NEW | 3.24 | 0.37 | 0.389 | 1.8 | 1.8 | NEMSOK - Object Layer Attributes #2, Status: Nový; Object Layer Attributes #2, Práce: Zateplovací systémy; Object Layer Attributes #2, Allright_Stavebni_dil_ID: 1402Okn0798460855; Object Layer Attributes #2, Jednotka: m2; Object Layer Attributes #2, Název_objektu: Okenní otvor
Okenní otvor | Půdorys 1.NP | Zateplovací systémy | 1402Okn0798460824 | m3 | Okenní otvor | NEW | 3.24 | 0.37 | 0.389 | 1.8 | 1.8 | NEMSOK - Object Layer Attributes #2, Status: Nový; Object Layer Attributes #2, Práce: Zateplovací systémy; Object Layer Attributes #2, Allright_Stavebni_dil_ID: 1402Okn0798460856; Object Layer Attributes #2, Jednotka: m2; Object Layer Attributes #2, Název_objektu: Okenní otvor
Okenní otvor | Půdorys 1.NP | Zateplovací systémy | 1402Okn0798465411 | m3 | Okenní otvor | NEW | 3.24 | 0.37 | 0.81 | 1.8 | 1.8 | NEMSOK - Object Layer Attributes #2, Status: Nový; Object Layer Attributes #2, Práce: Zateplovací systémy; Object Layer Attributes #2, Allright_Stavebni_dil_ID: 1402Okn0798467554; Object Layer Attributes #2, Jednotka: m2; Object Layer Attributes #2, Název_objektu: Okenní otvor
Okenní otvor | Půdorys 2.NP | Zateplovací systémy | 1502Okn0000000335 | m2 | Okenní otvor | NEW | 3.96 | 0.1 | 0.396 | 2.2 | 1.8
Okenní otvor | Půdorys 2.NP | Zateplovací systémy | 1502Okn0000000345 | m2 | Okenní otvor | NEW | 3.96 | 0.1 | 0.396 | 2.2 | 1.8
Okenní otvor | Půdorys 2.NP | Zateplovací systémy | 1502Okn0000001566 | m2 | Okenní otvor | NEW | 3.96 | 0.1 | 0.396 | 2.2 | 1.8
Okenní otvor | Půdorys 2.NP | Zateplovací systémy | 1502Okn0000004167 | m2 | Okenní otvor | NEW | 3.96 | 0.1 | 0.396 | 2.2 | 1.8
Okenní otvor | Půdorys 2.NP | Zateplovací systémy | 1502Okn0000004195 | m2 | Okenní otvor | NEW | 3.96 | 0.1 | 0.396 | 2.2 | 1.8
Okenní otvor | Půdorys 2.NP | Zateplovací systémy | 1502Okn0000004228 | m2 | Okenní otvor | NEW | 3.96 | 0.1 | 0.396 | 2.2 | 1.8
Okenní otvor | Půdorys 2.NP | Zateplovací systémy | 1502Okn0000004403 | m2 | Okenní otvor | NEW | 3.96 | 0.1 | 0.396 | 2.2 | 1.8
Okenní otvor | Půdorys 2.NP | Zateplovací systémy | 1502Okn0000004375 | m2 | Okenní otvor | NEW | 3.96 | 0.1 | 0.396 | 2.2 | 1.8
Okenní otvor | Půdorys 2.NP | Zateplovací systémy | 1502Okn0000004168 | m3 | Okenní otvor | NEW | 3.24 | 0.37 | 0.389 | 1.8 | 1.8 | NEMSOK - Object Layer Attributes #2, Status: Nový; Object Layer Attributes #2, Práce: Zateplovací systémy; Object Layer Attributes #2, Allright_Stavebni_dil_ID: 1502Okn0000004162; Object Layer Attributes #2, Jednotka: m2; Object Layer Attributes #2, Název_objektu: Okenní otvor
Okenní otvor | Půdorys 2.NP | Zateplovací systémy | 1502Okn0000004194 | m3 | Okenní otvor | NEW | 3.24 | 0.37 | 0.389 | 1.8 | 1.8 | NEMSOK - Object Layer Attributes #2, Status: Nový; Object Layer Attributes #2, Práce: Zateplovací systémy; Object Layer Attributes #2, Allright_Stavebni_dil_ID: 1502Okn0000004196; Object Layer Attributes #2, Jednotka: m2; Object Layer Attributes #2, Název_objektu: Okenní otvor
Okenní otvor | Půdorys 2.NP | Zateplovací systémy | 1502Okn0000004229 | m3 | Okenní otvor | NEW | 3.24 | 0.37 | 0.389 | 1.8 | 1.8 | NEMSOK - Object Layer Attributes #2, Status: Nový; Object Layer Attributes #2, Práce: Zateplovací systémy; Object Layer Attributes #2, Allright_Stavebni_dil_ID: 1502Okn0000004227; Object Layer Attributes #2, Jednotka: m2; Object Layer Attributes #2, Název_objektu: Okenní otvor
Okenní otvor | Půdorys 2.NP | Zateplovací systémy | 1502Okn0000004630 | m3 | Okenní otvor | NEW | 3.24 | 0.37 | 0.389 | 1.8 | 1.8 | NEMSOK - Object Layer Attributes #2, Status: Nový; Object Layer Attributes #2, Práce: Zateplovací systémy; Object Layer Attributes #2, Allright_Stavebni_dil_ID: 1502Okn0000004624; Object Layer Attributes #2, Jednotka: m2; Object Layer Attributes #2, Název_objektu: Okenní otvor
Okenní otvor | Půdorys 2.NP | Zateplovací systémy | 1502Okn0000000379 | m3 | Okenní otvor | NEW | 3.24 | 0.37 | 0.389 | 1.8 | 1.8 | NEMSOK - Object Layer Attributes #2, Status: Nový; Object Layer Attributes #2, Práce: Zateplovací systémy; Object Layer Attributes #2, Allright_Stavebni_dil_ID: 1502Okn0000000405; Object Layer Attributes #2, Jednotka: m2; Object Layer Attributes #2, Název_objektu: Okenní otvor
Okenní otvor | Půdorys 2.NP | Zateplovací systémy | 1502Okn0000005975 | m3 | Okenní otvor | NEW | 3.24 | 0.37 | 0.389 | 1.8 | 1.8 | NEMSOK - Object Layer Attributes #2, Status: Nový; Object Layer Attributes #2, Práce: Zateplovací systémy; Object Layer Attributes #2, Allright_Stavebni_dil_ID: 1502Okn0000005976; Object Layer Attributes #2, Jednotka: m2; Object Layer Attributes #2, Název_objektu: Okenní otvor
Okenní otvor | Půdorys 2.NP | Zateplovací systémy | 1502Okn0000004404 | m3 | Okenní otvor | NEW | 3.24 | 0.37 | 0.389 | 1.8 | 1.8 | NEMSOK - Object Layer Attributes #2, Status: Nový; Object Layer Attributes #2, Práce: Zateplovací systémy; Object Layer Attributes #2, Allright_Stavebni_dil_ID: 1502Okn0000004405; Object Layer Attributes #2, Jednotka: m2; Object Layer Attributes #2, Název_objektu: Okenní otvor
Okenní otvor | Půdorys 2.NP | Zateplovací systémy | 1502Okn0000004523 | m3 | Okenní otvor | NEW | 3.24 | 0.37 | 0.389 | 1.8 | 1.8 | NEMSOK - Object Layer Attributes #2, Status: Nový; Object Layer Attributes #2, Práce: Zateplovací systémy; Object Layer Attributes #2, Allright_Stavebni_dil_ID: 1502Okn0000004521; Object Layer Attributes #2, Jednotka: m2; Object Layer Attributes #2, Název_objektu: Okenní otvor
Okenní otvor | Půdorys 2.NP | Zateplovací systémy | 1514Okn0000000144 | m3 | Okenní otvor | NEW | 3.96 | 0.12 | 0.475 | 2.2 | 1.8 | NEMSOK - Object Layer Attributes #1, Označení: Okenní otvor; Object Layer Attributes #1, Systém kotvení: -
Okenní otvor | Půdorys 2.NP | Zateplovací systémy | 1514Okn0000000161 | m3 | Okenní otvor | NEW | 3.96 | 0.12 | 0.475 | 2.2 | 1.8 | NEMSOK - Object Layer Attributes #1, Označení: Okenní otvor; Object Layer Attributes #1, Systém kotvení: -
Okenní otvor | Půdorys 2.NP | Zateplovací systémy | 1514Okn0000000167 | m3 | Okenní otvor | NEW | 3.96 | 0.12 | 0.475 | 2.2 | 1.8 | NEMSOK - Object Layer Attributes #1, Označení: Okenní otvor; Object Layer Attributes #1, Systém kotvení: -
Okenní otvor | Půdorys 2.NP | Zateplovací systémy | 1514Okn0000000173 | m3 | Okenní otvor | NEW | 3.96 | 0.12 | 0.475 | 2.2 | 1.8 | NEMSOK - Object Layer Attributes #1, Označení: Okenní otvor; Object Layer Attributes #1, Systém kotvení: -
Dveřní otvor | Půdorys 1.PP | Betonářské práce | 1352Dve0000001545 | m3 | Dveřní otvor | NEW | 2.691 | 0.5 | 1.346 | 2.07 | 1.3 | NEMSOK - Object Layer Attributes #1, Směr otevírání dveří: -
Dveřní otvor | Půdorys 1.PP | Betonářské práce | 1352Dve0000001549 | m3 | Dveřní otvor | NEW | 2.691 | 0.5 | 1.346 | 2.07 | 1.3 | NEMSOK - Object Layer Attributes #1, Směr otevírání dveří: -
Dveřní otvor | Půdorys 1.PP | Betonářské práce | 1352Dve0000012277 | m3 | Dveřní otvor | NEW | 7.449 | 0.5 | 3.724 | 2.95 | 2.525 | NEMSOK - Object Layer Attributes #1, Směr otevírání dveří: -
Stěnová nika | Půdorys 1.PP | Zednické práce | 1352SNi0798449502 | m3 | Stěnová nika | NEW | 0.49 | 0.175 | 0.086 | 0.7 | 0.7
Dveřní otvor | Půdorys 1.PP | Betonářské práce | 1352Dve0000012853 | m3 | Dveřní otvor | NEW | 3.503 | 0.25 | 0.876 | 2.26 | 1.55 | NEMSOK - Object Layer Attributes #1, Směr otevírání dveří: -
Dveřní otvor | Půdorys 1.PP | Betonářské práce | 1352Dve0000012857 | m3 | Dveřní otvor | NEW | 3.503 | 0.25 | 0.876 | 2.26 | 1.55 | NEMSOK - Object Layer Attributes #1, Směr otevírání dveří: -
Prostup stěnou | Půdorys 1.PP | Betonářské práce | 1352SVý0000012753 | m3 | Stěnový výklenek | NEW | 0.24 | 0.2 | 0.048 | 0.6 | 0.4
Prostup stěnou | Půdorys 1.PP | Betonářské práce | 1352SVý0000012744 | m3 | Stěnový výklenek | NEW | 0.24 | 0.2 | 0.048 | 0.6 | 0.4
Prostup stěnou | Půdorys 1.PP | Betonářské práce | 1352SVý0000012716 | m3 | Stěnový výklenek | NEW | 0.24 | 0.2 | 0.048 | 0.6 | 0.4
Prostup stěnou | Půdorys 1.PP | Betonářské práce | 1352SVý0000012760 | m3 | Stěnový výklenek | NEW | 0.24 | 0.2 | 0.048 | 0.6 | 0.4
Prostup stěnou | Půdorys 1.PP | Betonářské práce | 1352SVý0000012769 | m3 | Stěnový výklenek | NEW | 0.24 | 0.2 | 0.048 | 0.6 | 0.4
Prostup stěnou | Půdorys 1.PP | Betonářské práce | 1352SVý0000012785 | m3 | Stěnový výklenek | NEW | 0.24 | 0.2 | 0.048 | 0.6 | 0.4
Prostup stěnou | Půdorys 1.PP | Betonářské práce | 1352SVý0000012797 | m3 | Stěnový výklenek | NEW | 0.24 | 0.2 | 0.048 | 0.6 | 0.4
Dveřní otvor | Půdorys 1.PP | Betonářské práce | 1352Dve0798437750 | m3 | Dveřní otvor | NEW | 1.818 | 0.125 | 0.227 | 2.02 | 0.9 | NEMSOK - Object Layer Attributes #1, Směr otevírání dveří: L
Okenní otvor | Půdorys 1.PP | Zateplovací systémy | 1352Okn0798440232 | m3 | Okenní otvor | NEW | 1.575 | 0.125 | 0.197 | 1.75 | 0.9
Okenní otvor | Půdorys 1.PP | Zateplovací systémy | 1352Okn0798441265 | m3 | Okenní otvor | NEW | 1.575 | 0.125 | 0.197 | 1.75 | 0.9
CHL | Půdorys 1.PP | Betonářské práce | 1352SVý0798502348 | m3 | Stěnový výklenek | NEW | 0.018 | 0.125 | 0.002 | 0.15 | 0.15 | NEMSOK - Object Layer Attributes #1, Označení: CHL
Okenní otvor | Půdorys 1.PP | Zateplovací systémy | 1352Okn0798458959 | m3 | Okenní otvor | NEW | 1.8 | 0.305 | 0.36 | 1.5 | 1.2 | NEMSOK - Object Layer Attributes #2, Status: Nový; Object Layer Attributes #2, Práce: Zateplovací systémy; Object Layer Attributes #2, Allright_Stavebni_dil_ID: 1352Okn0798458958; Object Layer Attributes #2, Jednotka: m2; Object Layer Attributes #2, Název_objektu: Okenní otvor; Object Layer Attributes #3, Status: Nový; Object Layer Attributes #3, Práce: Zateplovací systémy; Object Layer Attributes #3, Allright_Stavebni_dil_ID: 1352Okn0798458957; Object Layer Attributes #3, Jednotka: m2; Object Layer Attributes #3, Název_objektu: Okenní otvor
Okenní otvor | Půdorys 1.PP | Zateplovací systémy | 1352Okn0798431705 | m3 | Okenní otvor | NEW | 2.25 | 0.305 | 0.45 | 1.5 | 1.5 | NEMSOK - Object Layer Attributes #2, Status: Nový; Object Layer Attributes #2, Práce: Zateplovací systémy; Object Layer Attributes #2, Allright_Stavebni_dil_ID: 1352Okn0798431706; Object Layer Attributes #2, Jednotka: m2; Object Layer Attributes #2, Název_objektu: Okenní otvor; Object Layer Attributes #3, Status: Nový; Object Layer Attributes #3, Práce: Zateplovací systémy; Object Layer Attributes #3, Allright_Stavebni_dil_ID: 1352Okn0798431948; Object Layer Attributes #3, Jednotka: m2; Object Layer Attributes #3, Název_objektu: Okenní otvor
Okenní otvor | Půdorys 1.PP | Zateplovací systémy | 1352Okn0798472437 | m3 | Okenní otvor | NEW | 2.25 | 0.305 | 0.45 | 1.5 | 1.5 | NEMSOK - Object Layer Attributes #2, Status: Nový; Object Layer Attributes #2, Práce: Zateplovací systémy; Object Layer Attributes #2, Allright_Stavebni_dil_ID: 1352Okn0798472436; Object Layer Attributes #2, Jednotka: m2; Object Layer Attributes #2, Název_objektu: Okenní otvor; Object Layer Attributes #3, Status: Nový; Object Layer Attributes #3, Práce: Zateplovací systémy; Object Layer Attributes #3, Allright_Stavebni_dil_ID: 1352Okn0798472435; Object Layer Attributes #3, Jednotka: m2; Object Layer Attributes #3, Název_objektu: Okenní otvor
Okenní otvor | Půdorys 1.PP | Zateplovací systémy | 1352Okn0798472468 | m3 | Okenní otvor | NEW | 2.25 | 0.305 | 0.45 | 1.5 | 1.5 | NEMSOK - Object Layer Attributes #2, Status: Nový; Object Layer Attributes #2, Práce: Zateplovací systémy; Object Layer Attributes #2, Allright_Stavebni_dil_ID: 1352Okn0798472469; Object Layer Attributes #2, Jednotka: m2; Object Layer Attributes #2, Název_objektu: Okenní otvor; Object Layer Attributes #3, Status: Nový; Object Layer Attributes #3, Práce: Zateplovací systémy; Object Layer Attributes #3, Allright_Stavebni_dil_ID: 1352Okn0798472470; Object Layer Attributes #3, Jednotka: m2; Object Layer Attributes #3, Název_objektu: Okenní otvor
Okenní otvor | Půdorys 1.PP | Zateplovací systémy | 1352Okn0798444901 | m3 | Okenní otvor | NEW | 2.25 | 0.305 | 0.45 | 1.5 | 1.5 | NEMSOK - Object Layer Attributes #2, Status: Nový; Object Layer Attributes #2, Práce: Zateplovací systémy; Object Layer Attributes #2, Allright_Stavebni_dil_ID: 1352Okn0798444900; Object Layer Attributes #2, Jednotka: m2; Object Layer Attributes #2, Název_objektu: Okenní otvor; Object Layer Attributes #3, Status: Nový; Object Layer Attributes #3, Práce: Zateplovací systémy; Object Layer Attributes #3, Allright_Stavebni_dil_ID: 1352Okn0798444899; Object Layer Attributes #3, Jednotka: m2; Object Layer Attributes #3, Název_objektu: Okenní otvor
Okenní otvor | Půdorys 1.PP | Zateplovací systémy | 1352Okn0798445034 | m3 | Okenní otvor | NEW | 2.25 | 0.305 | 0.45 | 1.5 | 1.5 | NEMSOK - Object Layer Attributes #2, Status: Nový; Object Layer Attributes #2, Práce: Zateplovací systémy; Object Layer Attributes #2, Allright_Stavebni_dil_ID: 1352Okn0798445033; Object Layer Attributes #2, Jednotka: m2; Object Layer Attributes #2, Název_objektu: Okenní otvor; Object Layer Attributes #3, Status: Nový; Object Layer Attributes #3, Práce: Zateplovací systémy; Object Layer Attributes #3, Allright_Stavebni_dil_ID: 1352Okn0798445032; Object Layer Attributes #3, Jednotka: m2; Object Layer Attributes #3, Název_objektu: Okenní otvor
Okenní otvor | Půdorys 1.PP | Zateplovací systémy | 1352Okn0798466277 | m3 | Okenní otvor | NEW | 2.25 | 0.305 | 0.45 | 1.5 | 1.5 | NEMSOK - Object Layer Attributes #2, Status: Nový; Object Layer Attributes #2, Práce: Zateplovací systémy; Object Layer Attributes #2, Allright_Stavebni_dil_ID: 1352Okn0798466276; Object Layer Attributes #2, Jednotka: m2; Object Layer Attributes #2, Název_objektu: Okenní otvor; Object Layer Attributes #3, Status: Nový; Object Layer Attributes #3, Práce: Zateplovací systémy; Object Layer Attributes #3, Allright_Stavebni_dil_ID: 1352Okn0798466278; Object Layer Attributes #3, Jednotka: m2; Object Layer Attributes #3, Název_objektu: Okenní otvor
Okenní otvor | Půdorys 1.PP | Zateplovací systémy | 1352Okn0798472795 | m3 | Okenní otvor | NEW | 2.25 | 0.305 | 0.45 | 1.5 | 1.5 | NEMSOK - Object Layer Attributes #2, Status: Nový; Object Layer Attributes #2, Práce: Zateplovací systémy; Object Layer Attributes #2, Allright_Stavebni_dil_ID: 1352Okn0798472793; Object Layer Attributes #2, Jednotka: m2; Object Layer Attributes #2, Název_objektu: Okenní otvor; Object Layer Attributes #3, Status: Nový; Object Layer Attributes #3, Práce: Zateplovací systémy; Object Layer Attributes #3, Allright_Stavebni_dil_ID: 1352Okn0798472792; Object Layer Attributes #3, Jednotka: m2; Object Layer Attributes #3, Název_objektu: Okenní otvor
Okenní otvor | Půdorys 1.PP | Zateplovací systémy | 1352Okn0798472188 | m2 | Okenní otvor | NEW | 2.25 | 0.1 | 0.225 | 1.5 | 1.5
ZTI | Půdorys 1.PP | Betonářské práce | 1352SVý0798502902 | m3 | Stěnový výklenek | NEW | 0.063 | 0.125 | 0.008 | 0.17 | 0.37 | NEMSOK - Object Layer Attributes #1, Označení: ZTI
Okenní otvor | Půdorys 1.PP | Zateplovací systémy | 1352Okn0798443780 | m3 | Okenní otvor | NEW | 0.72 | 0.125 | 0.09 | 1.2 | 0.6
Dveřní otvor | Půdorys 1.PP | Betonářské práce | 1352Dve0798436818 | m3 | Dveřní otvor | NEW | 3.286 | 0.125 | 0.411 | 2.12 | 1.55 | NEMSOK - Object Layer Attributes #1, Směr otevírání dveří: -
UT | Půdorys 1.PP | Betonářské práce | 1352SVý0798501951 | m3 | Stěnový výklenek | NEW | 0.045 | 0.125 | 0.006 | 0.15 | 0.3 | NEMSOK - Object Layer Attributes #1, Označení: UT
Dveřní otvor | Půdorys 1.PP | Betonářské práce | 1352Dve0798450558 | m3 | Dveřní otvor | NEW | 2.2 | 0.125 | 0.275 | 2 | 1.1 | NEMSOK - Object Layer Attributes #1, Směr otevírání dveří: -
Okenní otvor | Půdorys 1.PP | Zateplovací systémy | 1352Okn0798444794 | m2 | Okenní otvor | NEW | 2.25 | 0.1 | 0.225 | 1.5 | 1.5
Okenní otvor | Půdorys 1.PP | Zateplovací systémy | 1352Okn0798450931 | m2 | Okenní otvor | NEW | 2.25 | 0.1 | 0.225 | 1.5 | 1.5
Okenní otvor | Půdorys 1.PP | Zateplovací systémy | 1352Okn0798480879 | m2 | Okenní otvor | NEW | 3.15 | 0.1 | 0.315 | 2.25 | 1.4
Dveřní otvor | Půdorys 1.PP | Betonářské práce | 1352Dve0000013286 | m3 | Dveřní otvor | NEW | 3.131 | 0.125 | 0.391 | 2.02 | 1.55 | NEMSOK - Object Layer Attributes #1, Směr otevírání dveří: -
Okenní otvor | Půdorys 1.PP | Zateplovací systémy | 1352Okn0798459400 | m2 | Okenní otvor | NEW | 1.8 | 0.1 | 0.18 | 1.5 | 1.2
Okenní otvor | Půdorys 1.PP | Zateplovací systémy | 1352Okn0798469312 | m3 | Okenní otvor | NEW | 0.48 | 0.125 | 0.06 | 1.2 | 0.4
Dveřní otvor | Půdorys 1.PP | Betonářské práce | 1352Dve0798459509 | m3 | Dveřní otvor | NEW | 2.424 | 0.125 | 0.303 | 2.02 | 1.2 | NEMSOK - Object Layer Attributes #1, Směr otevírání dveří: P
UT | Půdorys 1.PP | Betonářské práce | 1352SVý0798503226 | m3 | Stěnový výklenek | NEW | 0.03 | 0.125 | 0.004 | 0.12 | 0.25 | NEMSOK - Object Layer Attributes #1, Označení: UT; Object Layer Attributes #1, Kód prvku: SN07.02.0001; Object Layer Attributes #1, Podlaží: 1.PP
Dveřní otvor | Půdorys 1.PP | Betonářské práce | 1352Dve0798501047 | m3 | Dveřní otvor | NEW | 2.12 | 0.125 | 0.265 | 2.12 | 1 | NEMSOK - Object Layer Attributes #1, Směr otevírání dveří: -
Okenní otvor | Půdorys 1.PP | Zateplovací systémy | 1352Okn0798460657 | m3 | Okenní otvor | NEW | 0.72 | 0.125 | 0.09 | 1.2 | 0.6
UT | Půdorys 1.PP | Betonářské práce | 1352SVý0798503200 | m3 | Stěnový výklenek | NEW | 0.03 | 0.125 | 0.004 | 0.12 | 0.25 | NEMSOK - Object Layer Attributes #1, Označení: UT; Object Layer Attributes #1, Kód prvku: SN07.02.0001; Object Layer Attributes #1, Podlaží: 1.PP
Dveřní otvor | Půdorys 1.PP | Betonářské práce | 1352Dve0798460283 | m3 | Dveřní otvor | NEW | 1.414 | 0.125 | 0.177 | 2.02 | 0.7 | NEMSOK - Object Layer Attributes #1, Směr otevírání dveří: L
ZTI | Půdorys 1.PP | Betonářské práce | 1352SVý0798501765 | m3 | Stěnový výklenek | NEW | 0.008 | 0.125 | 0.001 | 0.1 | 0.1 | NEMSOK - Object Layer Attributes #1, Označení: ZTI
Dveřní otvor | Půdorys 1.PP | Betonářské práce | 1352Dve0798494092 | m3 | Dveřní otvor | NEW | 2.12 | 0.125 | 0.265 | 2.12 | 1 | NEMSOK - Object Layer Attributes #1, Směr otevírání dveří: -
Prostup stěnou | Půdorys 1.PP | Betonářské práce | 1352SVý0798503274 | m3 | Stěnový výklenek | NEW | 0.03 | 0.125 | 0.004 | 0.12 | 0.25 | NEMSOK - Object Layer Attributes #1, Kód prvku: SN07.02.0001; Object Layer Attributes #1, Podlaží: 1.PP
Dveřní otvor | Půdorys 1.PP | Betonářské práce | 1352Dve0798471302 | m3 | Dveřní otvor | NEW | 1.414 | 0.125 | 0.177 | 2.02 | 0.7 | NEMSOK - Object Layer Attributes #1, Směr otevírání dveří: P
Dveřní otvor | Půdorys 1.PP | Betonářské práce | 1352Dve0798471682 | m3 | Dveřní otvor | NEW | 2.424 | 0.125 | 0.303 | 2.02 | 1.2 | NEMSOK - Object Layer Attributes #1, Směr otevírání dveří: L
Dveřní otvor | Půdorys 1.PP | Betonářské práce | 1352Dve0798460488 | m3 | Dveřní otvor | NEW | 1.89 | 0.125 | 0.236 | 2.1 | 0.9 | NEMSOK - Object Layer Attributes #1, Směr otevírání dveří: -
Dveřní otvor | Půdorys 1.PP | Betonářské práce | 1352Dve0798460393 | m3 | Dveřní otvor | NEW | 1.414 | 0.125 | 0.177 | 2.02 | 0.7 | NEMSOK - Object Layer Attributes #1, Směr otevírání dveří: P
Dveřní otvor | Půdorys 1.PP | Betonářské práce | 1352Dve0798460338 | m3 | Dveřní otvor | NEW | 1.414 | 0.125 | 0.177 | 2.02 | 0.7 | NEMSOK - Object Layer Attributes #1, Směr otevírání dveří: L
Dveřní otvor | Půdorys 1.PP | Betonářské práce | 1352Dve0798460122 | m3 | Dveřní otvor | NEW | 2.424 | 0.125 | 0.303 | 2.02 | 1.2 | NEMSOK - Object Layer Attributes #1, Směr otevírání dveří: L
VZT | Půdorys 1.PP | Betonářské práce | 1352SVý0798502282 | m3 | Stěnový výklenek | NEW | 0.035 | 0.125 | 0.004 | 0.21 | 0.21 | NEMSOK - Object Layer Attributes #1, Označení: VZT
Dveřní otvor | Půdorys 1.PP | Betonářské práce | 1352Dve0798437071 | m3 | Dveřní otvor | NEW | 1.696 | 0.125 | 0.212 | 2.12 | 0.8 | NEMSOK - Object Layer Attributes #1, Směr otevírání dveří: -
Dveřní otvor | Půdorys 1.PP | Betonářské práce | 1352Dve0798449997 | m3 | Dveřní otvor | NEW | 1.54 | 0.125 | 0.192 | 2.2 | 0.7 | NEMSOK - Object Layer Attributes #1, Směr otevírání dveří: -
Dveřní otvor | Půdorys 1.PP | Betonářské práce | 1352Dve0798470444 | m3 | Dveřní otvor | NEW | 3.286 | 0.125 | 0.411 | 2.12 | 1.55 | NEMSOK - Object Layer Attributes #1, Směr otevírání dveří: -
Dveřní otvor | Půdorys 1.PP | Betonářské práce | 1352Dve0798471723 | m3 | Dveřní otvor | NEW | 3.131 | 0.125 | 0.391 | 2.02 | 1.55 | NEMSOK - Object Layer Attributes #1, Směr otevírání dveří: -
VZT | Půdorys 1.PP | Betonářské práce | 1352SVý0798502738 | m3 | Stěnový výklenek | NEW | 0.035 | 0.2 | 0.007 | 0.21 | 0.21 | NEMSOK - Object Layer Attributes #1, Označení: VZT
ZTI | Půdorys 1.PP | Betonářské práce | 1352SVý0798502714 | m3 | Stěnový výklenek | NEW | 0.063 | 0.2 | 0.013 | 0.17 | 0.37 | NEMSOK - Object Layer Attributes #1, Označení: ZTI
Okenní otvor | Půdorys 1.PP | Zateplovací systémy | 1352Okn0798440112 | m3 | Okenní otvor | NEW | 1.35 | 0.305 | 0.27 | 1.5 | 0.9 | NEMSOK - Object Layer Attributes #2, Status: Nový; Object Layer Attributes #2, Práce: Zateplovací systémy; Object Layer Attributes #2, Allright_Stavebni_dil_ID: 1352Okn0798440111; Object Layer Attributes #2, Jednotka: m2; Object Layer Attributes #2, Název_objektu: Okenní otvor; Object Layer Attributes #3, Status: Nový; Object Layer Attributes #3, Práce: Zateplovací systémy; Object Layer Attributes #3, Allright_Stavebni_dil_ID: 1352Okn0798440110; Object Layer Attributes #3, Jednotka: m2; Object Layer Attributes #3, Název_objektu: Okenní otvor
Okenní otvor | Půdorys 1.PP | Zateplovací systémy | 1352Okn0798441076 | m3 | Okenní otvor | NEW | 1.35 | 0.305 | 0.27 | 1.5 | 0.9 | NEMSOK - Object Layer Attributes #2, Status: Nový; Object Layer Attributes #2, Práce: Zateplovací systémy; Object Layer Attributes #2, Allright_Stavebni_dil_ID: 1352Okn0798441075; Object Layer Attributes #2, Jednotka: m2; Object Layer Attributes #2, Název_objektu: Okenní otvor; Object Layer Attributes #3, Status: Nový; Object Layer Attributes #3, Práce: Zateplovací systémy; Object Layer Attributes #3, Allright_Stavebni_dil_ID: 1352Okn0798441074; Object Layer Attributes #3, Jednotka: m2; Object Layer Attributes #3, Název_objektu: Okenní otvor
Okenní otvor | Půdorys 1.PP | Zateplovací systémy | 1352Okn0798468464 | m3 | Okenní otvor | NEW | 2.25 | 0.305 | 0.45 | 1.5 | 1.5 | NEMSOK - Object Layer Attributes #2, Status: Nový; Object Layer Attributes #2, Práce: Zateplovací systémy; Object Layer Attributes #2, Allright_Stavebni_dil_ID: 1352Okn0798468463; Object Layer Attributes #2, Jednotka: m2; Object Layer Attributes #2, Název_objektu: Okenní otvor; Object Layer Attributes #3, Status: Nový; Object Layer Attributes #3, Práce: Zateplovací systémy; Object Layer Attributes #3, Allright_Stavebni_dil_ID: 1352Okn0798468462; Object Layer Attributes #3, Jednotka: m2; Object Layer Attributes #3, Název_objektu: Okenní otvor
Prostup stěnou | Půdorys 1.PP | Betonářské práce | 1352SVý0798502358 | m3 | Stěnový výklenek | NEW | 0.018 | 0.305 | 0.001 | 0.15 | 0.15 | NEMSOK - Object Layer Attributes #2, Status: Nový; Object Layer Attributes #2, Práce: Betonářské práce; Object Layer Attributes #2, Allright_Stavebni_dil_ID: 1352SVý0798502357; Object Layer Attributes #2, Jednotka: m2; Object Layer Attributes #2, Název_objektu: Stěnový výklenek; Object Layer Attributes #1, Označení: CHL; Object Layer Attributes #3, Status: Nový; Object Layer Attributes #3, Práce: Betonářské práce; Object Layer Attributes #3, Allright_Stavebni_dil_ID: 1352SVý0798502356; Object Layer Attributes #3, Jednotka: m2; Object Layer Attributes #3, Název_objektu: Stěnový výklenek
Okenní otvor | Půdorys 1.PP | Zateplovací systémy | 1352Okn0798441173 | m3 | Okenní otvor | NEW | 1.35 | 0.305 | 0.27 | 1.5 | 0.9 | NEMSOK - Object Layer Attributes #2, Status: Nový; Object Layer Attributes #2, Práce: Zateplovací systémy; Object Layer Attributes #2, Allright_Stavebni_dil_ID: 1352Okn0798441172; Object Layer Attributes #2, Jednotka: m2; Object Layer Attributes #2, Název_objektu: Okenní otvor; Object Layer Attributes #3, Status: Nový; Object Layer Attributes #3, Práce: Zateplovací systémy; Object Layer Attributes #3, Allright_Stavebni_dil_ID: 1352Okn0798441171; Object Layer Attributes #3, Jednotka: m2; Object Layer Attributes #3, Název_objektu: Okenní otvor
Prostup stěnou | Půdorys 1.PP | Betonářské práce | 1352SVý0798502439 | m3 | Stěnový výklenek | NEW | 0.289 | 0.305 | 0.023 | 0.425 | 0.68 | NEMSOK - Object Layer Attributes #2, Status: Nový; Object Layer Attributes #2, Práce: Betonářské práce; Object Layer Attributes #2, Allright_Stavebni_dil_ID: 1352SVý0798502438; Object Layer Attributes #2, Jednotka: m2; Object Layer Attributes #2, Název_objektu: Stěnový výklenek; Object Layer Attributes #1, Označení: VZT; Object Layer Attributes #3, Status: Nový; Object Layer Attributes #3, Práce: Betonářské práce; Object Layer Attributes #3, Allright_Stavebni_dil_ID: 1352SVý0798502437; Object Layer Attributes #3, Jednotka: m2; Object Layer Attributes #3, Název_objektu: Stěnový výklenek
Okenní otvor | Půdorys 1.PP | Zateplovací systémy | 1352Okn0798441380 | m3 | Okenní otvor | NEW | 2.625 | 0.125 | 0.328 | 1.75 | 1.5
Okenní otvor | Půdorys 1.PP | Zateplovací systémy | 1352Okn0798469357 | m3 | Okenní otvor | NEW | 0.48 | 0.125 | 0.06 | 1.2 | 0.4
Okenní otvor | Půdorys 1.PP | Zateplovací systémy | 1352Okn0798469501 | m2 | Okenní otvor | NEW | 2.25 | 0.1 | 0.225 | 1.5 | 1.5
Okenní otvor | Půdorys 1.PP | Zateplovací systémy | 1352Okn0798469499 | m2 | Okenní otvor | NEW | 2.25 | 0.1 | 0.225 | 1.5 | 1.5
Dveřní otvor | Půdorys 1.PP | Betonářské práce | 1352Dve0798437832 | m3 | Dveřní otvor | NEW | 2.05 | 0.2 | 0.41 | 2.05 | 1 | NEMSOK - Object Layer Attributes #1, Směr otevírání dveří: -
UT+VZT | Půdorys 1.PP | Betonářské práce | 1352SVý0798501699 | m3 | Stěnový výklenek | NEW | 0.1 | 0.2 | 0.02 | 0.2 | 0.5 | NEMSOK - Object Layer Attributes #1, Označení: UT+VZT
Stěnová nika | Půdorys 1.PP | Betonářské práce | 1352SNi0798503169 | m3 | Stěnová nika | NEW | 0.004 | 0.2 | 0.001 | 0.07 | 0.07 | NEMSOK - Object Layer Attributes #1, Kód prvku: SN07.02.0001; Object Layer Attributes #1, Podlaží: 1.PP
Stěnová nika | Půdorys 1.PP | Betonářské práce | 1352SNi0798503190 | m3 | Stěnová nika | NEW | 0.004 | 0.2 | 0.001 | 0.07 | 0.07 | NEMSOK - Object Layer Attributes #1, Kód prvku: SN07.02.0001; Object Layer Attributes #1, Podlaží: 1.PP
Okenní otvor | Půdorys 1.PP | Zateplovací systémy | 1352Okn0798470371 | m3 | Okenní otvor | NEW | 0.72 | 0.125 | 0.09 | 1.2 | 0.6
Dveřní otvor | Půdorys 1.PP | Betonářské práce | 1352Dve0798473336 | m3 | Dveřní otvor | NEW | 1.414 | 0.125 | 0.177 | 2.02 | 0.7 | NEMSOK - Object Layer Attributes #1, Směr otevírání dveří: L
Dveřní otvor | Půdorys 1.PP | Betonářské práce | 1352Dve0798473171 | m3 | Dveřní otvor | NEW | 2.424 | 0.125 | 0.303 | 2.02 | 1.2 | NEMSOK - Object Layer Attributes #1, Směr otevírání dveří: P
Dveřní otvor | Půdorys 1.PP | Betonářské práce | 1352Dve0798473125 | m3 | Dveřní otvor | NEW | 1.818 | 0.125 | 0.227 | 2.02 | 0.9 | NEMSOK - Object Layer Attributes #1, Směr otevírání dveří: L
Okenní otvor | Půdorys 1.PP | Zateplovací systémy | 1352Okn0798470696 | m3 | Okenní otvor | NEW | 1.2 | 0.125 | 0.15 | 0.8 | 1.5
UT | Půdorys 1.PP | Betonářské práce | 1352SVý0798501295 | m3 | Stěnový výklenek | NEW | 0.09 | 0.125 | 0.011 | 0.15 | 0.6 | NEMSOK - Object Layer Attributes #1, Označení: UT
Okenní otvor | Půdorys 1.PP | Zateplovací systémy | 1352Okn0798471145 | m3 | Okenní otvor | NEW | 0.72 | 0.125 | 0.09 | 1.2 | 0.6
Dveřní otvor | Půdorys 1.PP | Betonářské práce | 1352Dve0798470718 | m3 | Dveřní otvor | NEW | 3.131 | 0.125 | 0.391 | 2.02 | 1.55 | NEMSOK - Object Layer Attributes #1, Směr otevírání dveří: -
Dveřní otvor | Půdorys 1.PP | Betonářské práce | 1352Dve0798449377 | m3 | Dveřní otvor | NEW | 3.131 | 0.125 | 0.391 | 2.02 | 1.55 | NEMSOK - Object Layer Attributes #1, Směr otevírání dveří: -
Dveřní otvor | Půdorys 1.PP | Betonářské práce | 1352Dve0798471348 | m3 | Dveřní otvor | NEW | 1.414 | 0.125 | 0.177 | 2.02 | 0.7 | NEMSOK - Object Layer Attributes #1, Směr otevírání dveří: P
Dveřní otvor | Půdorys 1.PP | Betonářské práce | 1352Dve0798472999 | m3 | Dveřní otvor | NEW | 1.818 | 0.125 | 0.227 | 2.02 | 0.9 | NEMSOK - Object Layer Attributes #1, Směr otevírání dveří: L
Dveřní otvor | Půdorys 1.PP | Betonářské práce | 1352Dve0798473045 | m3 | Dveřní otvor | NEW | 1.818 | 0.125 | 0.227 | 2.02 | 0.9 | NEMSOK - Object Layer Attributes #1, Směr otevírání dveří: P
Dveřní otvor | Půdorys 1.PP | Betonářské práce | 1352Dve0798471535 | m3 | Dveřní otvor | NEW | 2.424 | 0.125 | 0.303 | 2.02 | 1.2 | NEMSOK - Object Layer Attributes #1, Směr otevírání dveří: L
Dveřní otvor | Půdorys 1.PP | Betonářské práce | 1352Dve0798497661 | m3 | Dveřní otvor | NEW | 2.424 | 0.125 | 0.303 | 2.02 | 1.2 | NEMSOK - Object Layer Attributes #1, Směr otevírání dveří: P
Okenní otvor | Půdorys 1.PP | Zateplovací systémy | 1352Okn0798500075 | m3 | Okenní otvor | NEW | 0.72 | 0.125 | 0.09 | 1.2 | 0.6
Dveřní otvor | Půdorys 1.PP | Betonářské práce | 1352Dve0798472495 | m3 | Dveřní otvor | NEW | 2.424 | 0.125 | 0.303 | 2.02 | 1.2 | NEMSOK - Object Layer Attributes #1, Směr otevírání dveří: -
Okenní otvor | Půdorys 1.PP | Zateplovací systémy | 1352Okn0798472438 | m2 | Okenní otvor | NEW | 2.25 | 0.1 | 0.225 | 1.5 | 1.5
Okenní otvor | Půdorys 1.PP | Zateplovací systémy | 1352Okn0798472467 | m2 | Okenní otvor | NEW | 2.25 | 0.1 | 0.225 | 1.5 | 1.5
Okenní otvor | Půdorys 1.PP | Zateplovací systémy | 1352Okn0798449478 | m3 | Okenní otvor | NEW | 0.49 | 0.125 | 0.061 | 0.7 | 0.7
VZT | Půdorys 1.PP | Betonářské práce | 1352SVý0798502974 | m3 | Stěnový výklenek | NEW | 0.035 | 0.125 | 0.004 | 0.21 | 0.21 | NEMSOK - Object Layer Attributes #1, Označení: VZT
Dveřní otvor | Půdorys 1.PP | Betonářské práce | 1352Dve0798474149 | m3 | Dveřní otvor | NEW | 2.544 | 0.125 | 0.318 | 2.12 | 1.2 | NEMSOK - Object Layer Attributes #1, Směr otevírání dveří: -
Okenní otvor | Půdorys 1.PP | Zateplovací systémy | 1352Okn0798459122 | m2 | Okenní otvor | NEW | 1.8 | 0.1 | 0.18 | 1.5 | 1.2
Okenní otvor | Půdorys 1.PP | Zateplovací systémy | 1352Okn0798458822 | m3 | Okenní otvor | NEW | 1.8 | 0.305 | 0.36 | 1.5 | 1.2 | NEMSOK - Object Layer Attributes #2, Status: Nový; Object Layer Attributes #2, Práce: Zateplovací systémy; Object Layer Attributes #2, Allright_Stavebni_dil_ID: 1352Okn0798458821; Object Layer Attributes #2, Jednotka: m2; Object Layer Attributes #2, Název_objektu: Okenní otvor; Object Layer Attributes #3, Status: Nový; Object Layer Attributes #3, Práce: Zateplovací systémy; Object Layer Attributes #3, Allright_Stavebni_dil_ID: 1352Okn0798458820; Object Layer Attributes #3, Jednotka: m2; Object Layer Attributes #3, Název_objektu: Okenní otvor
Dveřní otvor | Půdorys 1.PP | Betonářské práce | 1352Dve0798460979 | m3 | Dveřní otvor | NEW | 2.081 | 0.1 | 0.208 | 2.02 | 1.03 | NEMSOK - Object Layer Attributes #1, Směr otevírání dveří: L
VZT | Půdorys 1.PP | Betonářské práce | 1352SVý0798502936 | m3 | Stěnový výklenek | NEW | 0.15 | 0.25 | 0.038 | 0.25 | 0.6 | NEMSOK - Object Layer Attributes #1, Označení: VZT
Dveřní otvor | Půdorys 1.PP | Betonářské práce | 1352Dve0798473384 | m3 | Dveřní otvor | NEW | 2.025 | 0.25 | 0.506 | 2.25 | 0.9 | NEMSOK - Object Layer Attributes #1, Směr otevírání dveří: -
Dveřní otvor | Půdorys 1.PP | Betonářské práce | 1352Dve0798444523 | m3 | Dveřní otvor | NEW | 2.475 | 0.25 | 0.619 | 2.25 | 1.1 | NEMSOK - Object Layer Attributes #1, Směr otevírání dveří: -
Dveřní otvor | Půdorys 1.PP | Betonářské práce | 1352Dve0798453453 | m3 | Dveřní otvor | NEW | 2.475 | 0.25 | 0.619 | 2.25 | 1.1 | NEMSOK - Object Layer Attributes #1, Směr otevírání dveří: -
Dveřní otvor | Půdorys 1.PP | Betonářské práce | 1352Dve0798453452 | m3 | Dveřní otvor | NEW | 2.475 | 0.25 | 0.619 | 2.25 | 1.1 | NEMSOK - Object Layer Attributes #1, Směr otevírání dveří: -
Dveřní otvor | Půdorys 1.PP | Betonářské práce | 1352Dve0798453458 | m3 | Dveřní otvor | NEW | 2.025 | 0.25 | 0.506 | 2.25 | 0.9 | NEMSOK - Object Layer Attributes #1, Směr otevírání dveří: -
Dveřní otvor | Půdorys 1.PP | Betonářské práce | 1352Dve0798482673 | m3 | Dveřní otvor | NEW | 2.7 | 0.25 | 0.675 | 2.25 | 1.2 | NEMSOK - Object Layer Attributes #1, Směr otevírání dveří: -
ZTI | Půdorys 1.PP | Betonářské práce | 1352SVý0798502759 | m3 | Stěnový výklenek | NEW | 0.063 | 0.25 | 0.016 | 0.17 | 0.37 | NEMSOK - Object Layer Attributes #1, Označení: ZTI
VZT | Půdorys 1.PP | Betonářské práce | 1352SVý0798502789 | m3 | Stěnový výklenek | NEW | 0.035 | 0.25 | 0.009 | 0.21 | 0.21 | NEMSOK - Object Layer Attributes #1, Označení: VZT
CHL | Půdorys 1.PP | Betonářské práce | 1352SVý0798502819 | m3 | Stěnový výklenek | NEW | 0.018 | 0.25 | 0.004 | 0.15 | 0.15 | NEMSOK - Object Layer Attributes #1, Označení: CHL
Dveřní otvor | Půdorys 1.PP | Betonářské práce | 1352Dve0798453454 | m3 | Dveřní otvor | NEW | 2.475 | 0.25 | 0.619 | 2.25 | 1.1 | NEMSOK - Object Layer Attributes #1, Směr otevírání dveří: -
VZT | Půdorys 1.PP | Betonářské práce | 1352SVý0798502843 | m3 | Stěnový výklenek | NEW | 0.035 | 0.25 | 0.009 | 0.21 | 0.21 | NEMSOK - Object Layer Attributes #1, Označení: VZT
ZTI | Půdorys 1.PP | Betonářské práce | 1352SVý0798502862 | m3 | Stěnový výklenek | NEW | 0.026 | 0.25 | 0.007 | 0.15 | 0.175 | NEMSOK - Object Layer Attributes #1, Označení: ZTI
Okenní otvor | Půdorys 1.PP | Zateplovací systémy | 1352Okn0798494330 | m3 | Okenní otvor | NEW | 0.09 | 0.125 | 0.011 | 0.3 | 0.3
ZTI | Půdorys 1.PP | Betonářské práce | 1352SVý0798501334 | m3 | Stěnový výklenek | NEW | 0.033 | 0.125 | 0.004 | 0.11 | 0.3 | NEMSOK - Object Layer Attributes #1, Označení: ZTI
Dveřní otvor | Půdorys 1.PP | Betonářské práce | 1352Dve0798460168 | m3 | Dveřní otvor | NEW | 1.818 | 0.125 | 0.227 | 2.02 | 0.9 | NEMSOK - Object Layer Attributes #1, Směr otevírání dveří: -
Dveřní otvor | Půdorys 1.PP | Betonářské práce | 1352Dve0798460214 | m3 | Dveřní otvor | NEW | 2.424 | 0.125 | 0.303 | 2.02 | 1.2 | NEMSOK - Object Layer Attributes #1, Směr otevírání dveří: -
Dveřní otvor | Půdorys 1.PP | Betonářské práce | 1352Dve0798475036 | m3 | Dveřní otvor | NEW | 3 | 0.305 | 0.6 | 2.5 | 1.2 | NEMSOK - Object Layer Attributes #1, Směr otevírání dveří: -; Object Layer Attributes #2, Status: Nový; Object Layer Attributes #2, Práce: Betonářské práce; Object Layer Attributes #2, Allright_Stavebni_dil_ID: 1352Dve0798475035; Object Layer Attributes #2, Jednotka: m2; Object Layer Attributes #2, Název_objektu: Dveřní otvor; Object Layer Attributes #2, Směr otevírání dveří: -; Object Layer Attributes #3, Status: Nový; Object Layer Attributes #3, Práce: Betonářské práce; Object Layer Attributes #3, Allright_Stavebni_dil_ID: 1352Dve0798475034; Object Layer Attributes #3, Jednotka: m2; Object Layer Attributes #3, Název_objektu: Dveřní otvor; Object Layer Attributes #3, Směr otevírání dveří: -
Prostup stěnou | Půdorys 1.PP | Betonářské práce | 1352SVý0798501866 | m3 | Stěnový výklenek | NEW | 0.071 | 0.225 | 0.014 | 0.3 | 0.3 | NEMSOK - Object Layer Attributes #2, Status: Nový; Object Layer Attributes #2, Práce: Betonářské práce; Object Layer Attributes #2, Allright_Stavebni_dil_ID: 1352SVý0798501867; Object Layer Attributes #2, Jednotka: m2; Object Layer Attributes #2, Název_objektu: Stěnový výklenek
Prostup stěnou | Půdorys 1.PP | Betonářské práce | 1352SVý0798501839 | m3 | Stěnový výklenek | NEW | 0.008 | 0.225 | 0.002 | 0.1 | 0.1 | NEMSOK - Object Layer Attributes #2, Status: Nový; Object Layer Attributes #2, Práce: Betonářské práce; Object Layer Attributes #2, Allright_Stavebni_dil_ID: 1352SVý0798501840; Object Layer Attributes #2, Jednotka: m2; Object Layer Attributes #2, Název_objektu: Stěnový výklenek
Prostup stěnou | Půdorys 1.PP | Betonářské práce | 1352SVý0798501431 | m3 | Stěnový výklenek | NEW | 0.045 | 0.225 | 0.009 | 0.15 | 0.3 | NEMSOK - Object Layer Attributes #2, Status: Nový; Object Layer Attributes #2, Práce: Betonářské práce; Object Layer Attributes #2, Allright_Stavebni_dil_ID: 1352SVý0798501432; Object Layer Attributes #2, Jednotka: m2; Object Layer Attributes #2, Název_objektu: Stěnový výklenek
ZTI | Půdorys 1.PP | Betonářské práce | 1352SVý0798501450 | m3 | Stěnový výklenek | NEW | 0.033 | 0.225 | 0.007 | 0.11 | 0.3 | NEMSOK - Object Layer Attributes #2, Status: Nový; Object Layer Attributes #2, Práce: Betonářské práce; Object Layer Attributes #2, Allright_Stavebni_dil_ID: 1352SVý0798501451; Object Layer Attributes #2, Jednotka: m2; Object Layer Attributes #2, Název_objektu: Stěnový výklenek; Object Layer Attributes #1, Označení: ZTI
Dveřní otvor | Půdorys 1.PP | Betonářské práce | 1352Dve0798475299 | m3 | Dveřní otvor | NEW | 3 | 0.305 | 0.6 | 2.5 | 1.2 | NEMSOK - Object Layer Attributes #1, Směr otevírání dveří: -; Object Layer Attributes #2, Status: Nový; Object Layer Attributes #2, Práce: Betonářské práce; Object Layer Attributes #2, Allright_Stavebni_dil_ID: 1352Dve0798475298; Object Layer Attributes #2, Jednotka: m2; Object Layer Attributes #2, Název_objektu: Dveřní otvor; Object Layer Attributes #2, Směr otevírání dveří: -; Object Layer Attributes #3, Status: Nový; Object Layer Attributes #3, Práce: Betonářské práce; Object Layer Attributes #3, Allright_Stavebni_dil_ID: 1352Dve0798475297; Object Layer Attributes #3, Jednotka: m2; Object Layer Attributes #3, Název_objektu: Dveřní otvor; Object Layer Attributes #3, Směr otevírání dveří: -
Dveřní otvor | Půdorys 1.PP | Betonářské práce | 1352Dve0000004731 | m3 | Dveřní otvor | NEW | 4.32 | 0.305 | 0.864 | 2.4 | 1.8 | NEMSOK - Object Layer Attributes #1, Směr otevírání dveří: -; Object Layer Attributes #2, Status: Nový; Object Layer Attributes #2, Práce: Betonářské práce; Object Layer Attributes #2, Allright_Stavebni_dil_ID: 1352Dve0000004730; Object Layer Attributes #2, Jednotka: m2; Object Layer Attributes #2, Název_objektu: Dveřní otvor; Object Layer Attributes #2, Směr otevírání dveří: -; Object Layer Attributes #3, Status: Nový; Object Layer Attributes #3, Práce: Betonářské práce; Object Layer Attributes #3, Allright_Stavebni_dil_ID: 1352Dve0798433613; Object Layer Attributes #3, Jednotka: m2; Object Layer Attributes #3, Název_objektu: Dveřní otvor; Object Layer Attributes #3, Směr otevírání dveří: -
Dveřní otvor | Půdorys 1.PP | Betonářské práce | 1352Dve0798496620 | m3 | Dveřní otvor | NEW | 2.121 | 0.125 | 0.265 | 2.02 | 1.05 | NEMSOK - Object Layer Attributes #1, Směr otevírání dveří: -
Okenní otvor | Půdorys 1.PP | Zateplovací systémy | 1352Okn0798496893 | m3 | Okenní otvor | NEW | 1.305 | 0.125 | 0.163 | 1.2 | 1.088
Dveřní otvor | Půdorys 1.PP | Betonářské práce | 1352Dve0798496977 | m3 | Dveřní otvor | NEW | 1.414 | 0.125 | 0.177 | 2.02 | 0.7 | NEMSOK - Object Layer Attributes #1, Směr otevírání dveří: L
Dveřní otvor | Půdorys 1.PP | Betonářské práce | 1352Dve0798496999 | m3 | Dveřní otvor | NEW | 1.212 | 0.125 | 0.152 | 2.02 | 0.6 | NEMSOK - Object Layer Attributes #1, Směr otevírání dveří: -
Okenní otvor | Půdorys 1.PP | Zateplovací systémy | 1352Okn0798498646 | m3 | Okenní otvor | NEW | 0.66 | 0.125 | 0.082 | 1.2 | 0.55
Dveřní otvor | Půdorys 1.PP | Betonářské práce | 1352Dve0798497342 | m3 | Dveřní otvor | NEW | 1.414 | 0.125 | 0.177 | 2.02 | 0.7 | NEMSOK - Object Layer Attributes #1, Směr otevírání dveří: P
Dveřní otvor | Půdorys 1.PP | Betonářské práce | 1352Dve0798500217 | m3 | Dveřní otvor | NEW | 3.2 | 0.125 | 0.4 | 2 | 1.6 | NEMSOK - Object Layer Attributes #1, Směr otevírání dveří: -
Dveřní otvor | Půdorys 1.PP | Betonářské práce | 1352Dve0798500224 | m3 | Dveřní otvor | NEW | 3.272 | 0.125 | 0.409 | 2.02 | 1.62 | NEMSOK - Object Layer Attributes #1, Směr otevírání dveří: -
Dveřní otvor | Půdorys 1.PP | Betonářské práce | 1352Dve0798500231 | m3 | Dveřní otvor | NEW | 3.272 | 0.125 | 0.409 | 2.02 | 1.62 | NEMSOK - Object Layer Attributes #1, Směr otevírání dveří: -
Dveřní otvor | Půdorys 1.PP | Betonářské práce | 1352Dve0798497635 | m3 | Dveřní otvor | NEW | 2.424 | 0.125 | 0.303 | 2.02 | 1.2 | NEMSOK - Object Layer Attributes #1, Směr otevírání dveří: -
Dveřní otvor | Půdorys 1.PP | Betonářské práce | 1352Dve0798497434 | m3 | Dveřní otvor | NEW | 1.818 | 0.125 | 0.227 | 2.02 | 0.9 | NEMSOK - Object Layer Attributes #1, Směr otevírání dveří: P
Okenní otvor | Půdorys 1.PP | Zateplovací systémy | 1352Okn0798498599 | m3 | Okenní otvor | NEW | 0.72 | 0.125 | 0.09 | 1.2 | 0.6
Dveřní otvor | Půdorys 1.PP | Betonářské práce | 1352Dve0798500113 | m3 | Dveřní otvor | NEW | 2.424 | 0.125 | 0.303 | 2.02 | 1.2 | NEMSOK - Object Layer Attributes #1, Směr otevírání dveří: P
Okenní otvor | Půdorys 1.PP | Zateplovací systémy | 1352Okn0798483696 | m3 | Okenní otvor | NEW | 1.8 | 0.305 | 0.36 | 1.2 | 1.5 | NEMSOK - Object Layer Attributes #2, Status: Nový; Object Layer Attributes #2, Práce: Zateplovací systémy; Object Layer Attributes #2, Allright_Stavebni_dil_ID: 1352Okn0798483700; Object Layer Attributes #2, Jednotka: m2; Object Layer Attributes #2, Název_objektu: Okenní otvor; Object Layer Attributes #3, Status: Nový; Object Layer Attributes #3, Práce: Zateplovací systémy; Object Layer Attributes #3, Allright_Stavebni_dil_ID: 1352Okn0798483702; Object Layer Attributes #3, Jednotka: m2; Object Layer Attributes #3, Název_objektu: Okenní otvor
Okenní otvor | Půdorys 1.PP | Zateplovací systémy | 1352Okn0798474053 | m3 | Okenní otvor | NEW | 1.8 | 0.305 | 0.36 | 1.2 | 1.5 | NEMSOK - Object Layer Attributes #2, Status: Nový; Object Layer Attributes #2, Práce: Zateplovací systémy; Object Layer Attributes #2, Allright_Stavebni_dil_ID: 1352Okn0798474049; Object Layer Attributes #2, Jednotka: m2; Object Layer Attributes #2, Název_objektu: Okenní otvor; Object Layer Attributes #3, Status: Nový; Object Layer Attributes #3, Práce: Zateplovací systémy; Object Layer Attributes #3, Allright_Stavebni_dil_ID: 1352Okn0798474048; Object Layer Attributes #3, Jednotka: m2; Object Layer Attributes #3, Název_objektu: Okenní otvor
Okenní otvor | Půdorys 1.PP | Zateplovací systémy | 1352Okn0798483733 | m3 | Okenní otvor |  | 1.8 | 0.305 | 0.36 | 1.2 | 1.5 | NEMSOK - Object Layer Attributes #2, Práce: Zateplovací systémy; Object Layer Attributes #2, Allright_Stavebni_dil_ID: 1352Okn0798483731; Object Layer Attributes #2, Jednotka: m2; Object Layer Attributes #2, Název_objektu: Okenní otvor; Object Layer Attributes #3, Práce: Zateplovací systémy; Object Layer Attributes #3, Allright_Stavebni_dil_ID: 1352Okn0798483729; Object Layer Attributes #3, Jednotka: m2; Object Layer Attributes #3, Název_objektu: Okenní otvor
Okenní otvor | Půdorys 1.PP | Zateplovací systémy | 1352Okn0798474074 | m3 | Okenní otvor | NEW | 1.8 | 0.305 | 0.36 | 1.2 | 1.5 | NEMSOK - Object Layer Attributes #2, Status: Nový; Object Layer Attributes #2, Práce: Zateplovací systémy; Object Layer Attributes #2, Allright_Stavebni_dil_ID: 1352Okn0798474076; Object Layer Attributes #2, Jednotka: m2; Object Layer Attributes #2, Název_objektu: Okenní otvor; Object Layer Attributes #3, Status: Nový; Object Layer Attributes #3, Práce: Zateplovací systémy; Object Layer Attributes #3, Allright_Stavebni_dil_ID: 1352Okn0798474077; Object Layer Attributes #3, Jednotka: m2; Object Layer Attributes #3, Název_objektu: Okenní otvor
Okenní otvor | Půdorys 1.PP | Zateplovací systémy | 1352Okn0798483723 | m3 | Okenní otvor | NEW | 1.8 | 0.305 | 0.36 | 1.2 | 1.5 | NEMSOK - Object Layer Attributes #2, Status: Nový; Object Layer Attributes #2, Práce: Zateplovací systémy; Object Layer Attributes #2, Allright_Stavebni_dil_ID: 1352Okn0798483719; Object Layer Attributes #2, Jednotka: m2; Object Layer Attributes #2, Název_objektu: Okenní otvor; Object Layer Attributes #3, Status: Nový; Object Layer Attributes #3, Práce: Zateplovací systémy; Object Layer Attributes #3, Allright_Stavebni_dil_ID: 1352Okn0798483717; Object Layer Attributes #3, Jednotka: m2; Object Layer Attributes #3, Název_objektu: Okenní otvor
Prostup stěnou | Půdorys 1.PP | Betonářské práce | 1352SVý0798501237 | m3 | Stěnový výklenek | NEW | 0.045 | 0.305 | 0.004 | 0.15 | 0.3 | NEMSOK - Object Layer Attributes #2, Status: Nový; Object Layer Attributes #2, Práce: Betonářské práce; Object Layer Attributes #2, Allright_Stavebni_dil_ID: 1352SVý0798501236; Object Layer Attributes #2, Jednotka: m2; Object Layer Attributes #2, Název_objektu: Stěnový výklenek; Object Layer Attributes #3, Status: Nový; Object Layer Attributes #3, Práce: Betonářské práce; Object Layer Attributes #3, Allright_Stavebni_dil_ID: 1352SVý0798501235; Object Layer Attributes #3, Jednotka: m2; Object Layer Attributes #3, Název_objektu: Stěnový výklenek
Prostup stěnou | Půdorys 1.PP | Betonářské práce | 1352SVý0798501277 | m3 | Stěnový výklenek | NEW | 0.045 | 0.305 | 0.004 | 0.15 | 0.3 | NEMSOK - Object Layer Attributes #2, Status: Nový; Object Layer Attributes #2, Práce: Betonářské práce; Object Layer Attributes #2, Allright_Stavebni_dil_ID: 1352SVý0798501276; Object Layer Attributes #2, Jednotka: m2; Object Layer Attributes #2, Název_objektu: Stěnový výklenek; Object Layer Attributes #3, Status: Nový; Object Layer Attributes #3, Práce: Betonářské práce; Object Layer Attributes #3, Allright_Stavebni_dil_ID: 1352SVý0798501275; Object Layer Attributes #3, Jednotka: m2; Object Layer Attributes #3, Název_objektu: Stěnový výklenek
Okenní otvor | Půdorys 1.PP | Zateplovací systémy | 1352Okn0000004951 | m3 | Okenní otvor | NEW | 1.2 | 0.555 | 0.54 | 0.8 | 1.5 | NEMSOK - Object Layer Attributes #2, Status: Nový; Object Layer Attributes #2, Práce: Zateplovací systémy; Object Layer Attributes #2, Allright_Stavebni_dil_ID: 1352Okn0000004950; Object Layer Attributes #2, Jednotka: m2; Object Layer Attributes #2, Název_objektu: Okenní otvor; Object Layer Attributes #3, Status: Nový; Object Layer Attributes #3, Práce: Zateplovací systémy; Object Layer Attributes #3, Allright_Stavebni_dil_ID: 1352Okn0798429647; Object Layer Attributes #3, Jednotka: m2; Object Layer Attributes #3, Název_objektu: Okenní otvor
Dveřní otvor | Půdorys 1.PP | Betonářské práce | 1352Dve0798483009 | m3 | Dveřní otvor | NEW | 2.7 | 0.25 | 0.675 | 2.25 | 1.2 | NEMSOK - Object Layer Attributes #1, Směr otevírání dveří: -
ZTI+VZT | Půdorys 1.PP | Betonářské práce | 1352SVý0798502505 | m3 | Stěnový výklenek | NEW | 0.18 | 0.25 | 0.045 | 0.25 | 0.72 | NEMSOK - Object Layer Attributes #1, Označení: ZTI+VZT
Dveřní otvor | Půdorys 1.PP | Betonářské práce | 1352Dve0798447748 | m3 | Dveřní otvor | NEW | 2.025 | 0.25 | 0.506 | 2.25 | 0.9 | NEMSOK - Object Layer Attributes #1, Směr otevírání dveří: -
VZT | Půdorys 1.PP | Betonářské práce | 1352SVý0798502592 | m3 | Stěnový výklenek | NEW | 0.065 | 0.25 | 0.016 | 0.25 | 0.26 | NEMSOK - Object Layer Attributes #1, Označení: VZT
ELE | Půdorys 1.PP | Betonářské práce | 1352SVý0798503281 | m3 | Stěnový výklenek | NEW | 0.038 | 0.25 | 0.009 | 0.15 | 0.25 | NEMSOK - Object Layer Attributes #1, Označení: ELE
Dveřní otvor | Půdorys 1.PP | Betonářské práce | 1352Dve0798447086 | m3 | Dveřní otvor | NEW | 3.15 | 0.25 | 0.788 | 2.25 | 1.4 | NEMSOK - Object Layer Attributes #1, Směr otevírání dveří: -
Okenní otvor | Půdorys 1.PP | Zateplovací systémy | 1352Okn0798482338 | m2 | Okenní otvor | NEW | 3.15 | 0.1 | 0.315 | 2.25 | 1.4
Okenní otvor | Půdorys 1.PP | Zateplovací systémy | 1352Okn0798495510 | m3 | Okenní otvor | NEW | 1.35 | 0.305 | 0.27 | 1.5 | 0.9 | NEMSOK - Object Layer Attributes #2, Status: Nový; Object Layer Attributes #2, Práce: Zateplovací systémy; Object Layer Attributes #2, Allright_Stavebni_dil_ID: 1352Okn0798495515; Object Layer Attributes #2, Jednotka: m2; Object Layer Attributes #2, Název_objektu: Okenní otvor; Object Layer Attributes #3, Status: Nový; Object Layer Attributes #3, Práce: Zateplovací systémy; Object Layer Attributes #3, Allright_Stavebni_dil_ID: 1352Okn0798495514; Object Layer Attributes #3, Jednotka: m2; Object Layer Attributes #3, Název_objektu: Okenní otvor
Okenní otvor | Půdorys 1.PP | Zateplovací systémy | 1352Okn0798495509 | m3 | Okenní otvor |  | 1.35 | 0.305 | 0.27 | 1.5 | 0.9 | NEMSOK - Object Layer Attributes #2, Práce: Zateplovací systémy; Object Layer Attributes #2, Allright_Stavebni_dil_ID: 1352Okn0798495516; Object Layer Attributes #2, Jednotka: m2; Object Layer Attributes #2, Název_objektu: Okenní otvor; Object Layer Attributes #3, Práce: Zateplovací systémy; Object Layer Attributes #3, Allright_Stavebni_dil_ID: 1352Okn0798495517; Object Layer Attributes #3, Jednotka: m2; Object Layer Attributes #3, Název_objektu: Okenní otvor
Okenní otvor | Půdorys 1.PP | Zateplovací systémy | 1352Okn0798495511 | m3 | Okenní otvor | NEW | 1.35 | 0.305 | 0.27 | 1.5 | 0.9 | NEMSOK - Object Layer Attributes #2, Status: Nový; Object Layer Attributes #2, Práce: Zateplovací systémy; Object Layer Attributes #2, Allright_Stavebni_dil_ID: 1352Okn0798495512; Object Layer Attributes #2, Jednotka: m2; Object Layer Attributes #2, Název_objektu: Okenní otvor; Object Layer Attributes #3, Status: Nový; Object Layer Attributes #3, Práce: Zateplovací systémy; Object Layer Attributes #3, Allright_Stavebni_dil_ID: 1352Okn0798495513; Object Layer Attributes #3, Jednotka: m2; Object Layer Attributes #3, Název_objektu: Okenní otvor
Prostup stěnou | Půdorys 1.PP | Betonářské práce | 1352SVý0798501737 | m3 | Stěnový výklenek | NEW | 0.031 | 0.5 | 0.013 | 0.2 | 0.2 | NEMSOK - Object Layer Attributes #2, Status: Nový; Object Layer Attributes #2, Práce: Betonářské práce; Object Layer Attributes #2, Allright_Stavebni_dil_ID: 1352SVý0798501738; Object Layer Attributes #2, Jednotka: m2; Object Layer Attributes #2, Název_objektu: Stěnový výklenek; Object Layer Attributes #1, Označení: ZTI; Object Layer Attributes #3, Status: Nový; Object Layer Attributes #3, Práce: Betonářské práce; Object Layer Attributes #3, Allright_Stavebni_dil_ID: 1352SVý0798501739; Object Layer Attributes #3, Jednotka: m2; Object Layer Attributes #3, Název_objektu: Stěnový výklenek
Dveřní otvor | Půdorys 1.PP | Betonářské práce | 1352Dve0798475237 | m2 | Dveřní otvor | NEW | 3 | 0.1 | 0.3 | 2.5 | 1.2 | NEMSOK - Object Layer Attributes #1, Směr otevírání dveří: -
Prostup stěnou | Půdorys 1.PP | Betonářské práce | 1352SVý0798501858 | m2 | Stěnový výklenek | NEW | 0.071 | 0.1 | 0.007 | 0.3 | 0.3
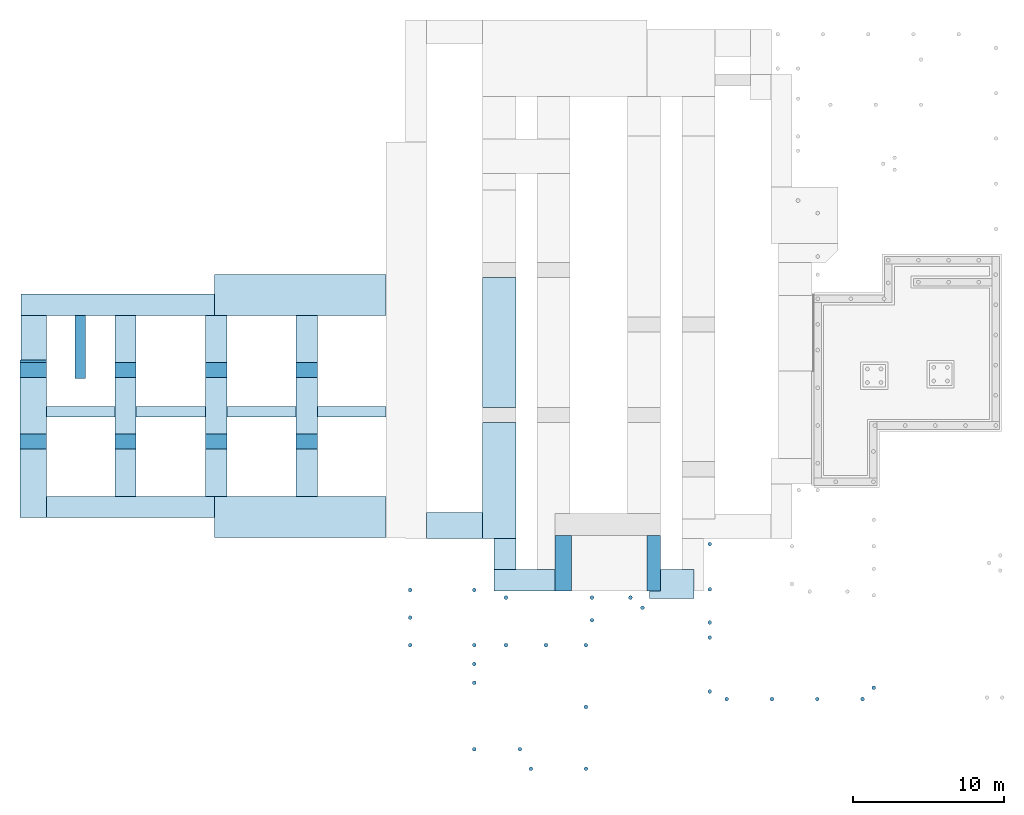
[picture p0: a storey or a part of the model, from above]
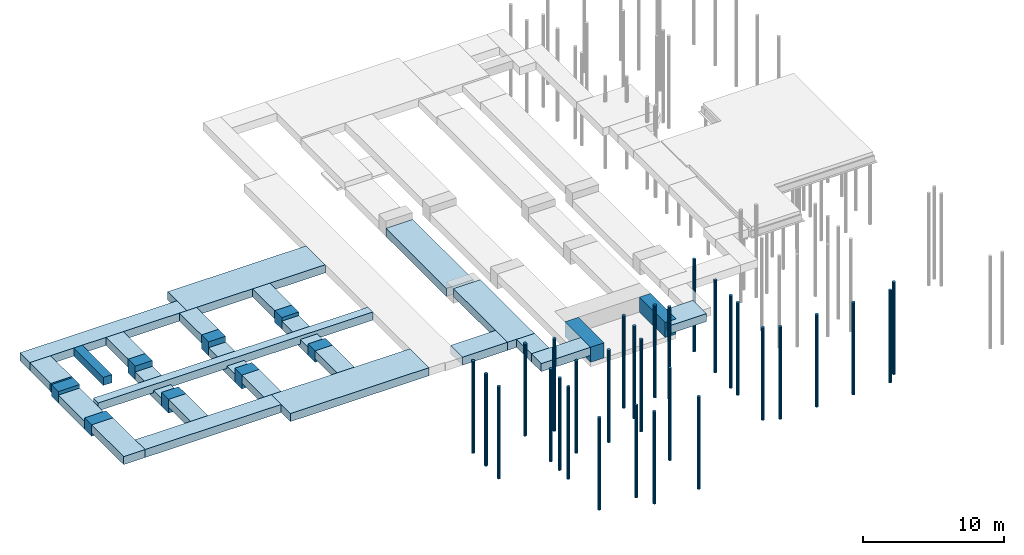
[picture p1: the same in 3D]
Properties of the parts of a building model (IFC4), part 14 of 45

# IfcOpeningElement: Opening (1638)
Name | In | Object Layer Attributes #1, Práce | Object Layer Attributes #1, Allright_Stavebni_dil_ID | Object Layer Attributes #1, Jednotka | Object Layer Attributes #1, Název_objektu | Status | Area (m2) | Depth (m) | Volume (m3) | Height (m) | Width (m)
Prostup stěnou | Půdorys 1.PP | Betonářské práce | 1352SVý0798501227 | m2 | Stěnový výklenek | NEW | 0.045 | 0.1 | 0.005 | 0.15 | 0.3
Prostup stěnou | Půdorys 1.PP | Betonářské práce | 1352SVý0798501278 | m2 | Stěnový výklenek | NEW | 0.045 | 0.1 | 0.005 | 0.15 | 0.3
Prostup stěnou | Půdorys 1.PP | Betonářské práce | 1352SVý0798501354 | m2 | Stěnový výklenek | NEW | 0.045 | 0.1 | 0.005 | 0.15 | 0.3
Prostup stěnou | Půdorys 1.PP | Betonářské práce | 1352SVý0798501776 | m2 | Stěnový výklenek | NEW | 0.008 | 0.1 | 0.001 | 0.1 | 0.1
ZTI | Půdorys 1.PP | Betonářské práce | 1352SVý0798501374 | m2 | Stěnový výklenek | NEW | 0.033 | 0.1 | 0.003 | 0.11 | 0.3 | NEMSOK - Object Layer Attributes #1, Označení: ZTI
Dveřní otvor | Půdorys 1.PP | Betonářské práce | 1352Dve0798475300 | m2 | Dveřní otvor | NEW | 3 | 0.1 | 0.3 | 2.5 | 1.2 | NEMSOK - Object Layer Attributes #1, Směr otevírání dveří: -
UT+VZT | Půdorys 1.PP | Betonářské práce | 1352SVý0798501959 | m3 | Stěnový výklenek | NEW | 0.27 | 0.125 | 0.034 | 0.25 | 1.08 | NEMSOK - Object Layer Attributes #1, Označení: UT+VZT
Dveřní otvor | Půdorys 1.PP | Betonářské práce | 1352Dve0798450267 | m3 | Dveřní otvor | NEW | 3.286 | 0.125 | 0.411 | 2.12 | 1.55 | NEMSOK - Object Layer Attributes #1, Směr otevírání dveří: -
Dveřní otvor | Půdorys 1.PP | Betonářské práce | 1352Dve0798450603 | m3 | Dveřní otvor | NEW | 3.105 | 0.125 | 0.388 | 2.3 | 1.35 | NEMSOK - Object Layer Attributes #1, Směr otevírání dveří: -
Dveřní otvor | Půdorys 1.PP | Betonářské práce | 1352Dve0798472106 | m3 | Dveřní otvor | NEW | 2.424 | 0.125 | 0.303 | 2.02 | 1.2 | NEMSOK - Object Layer Attributes #1, Směr otevírání dveří: P
Dveřní otvor | Půdorys 1.PP | Betonářské práce | 1352Dve0798472512 | m3 | Dveřní otvor | NEW | 1.818 | 0.125 | 0.227 | 2.02 | 0.9 | NEMSOK - Object Layer Attributes #1, Směr otevírání dveří: P
Okenní otvor | Půdorys 1.PP | Zateplovací systémy | 1352Okn0798496638 | m3 | Okenní otvor | NEW | 0.72 | 0.125 | 0.09 | 1.2 | 0.6
Okenní otvor | Půdorys 1.PP | Zateplovací systémy | 1352Okn0798496658 | m3 | Okenní otvor | NEW | 0.72 | 0.125 | 0.09 | 1.2 | 0.6
Dveřní otvor | Půdorys 1.PP | Betonářské práce | 1352Dve0798450427 | m3 | Dveřní otvor | NEW | 2.424 | 0.125 | 0.303 | 2.02 | 1.2 | NEMSOK - Object Layer Attributes #1, Směr otevírání dveří: -
UT | Půdorys 1.PP | Betonářské práce | 1352SVý0798501314 | m3 | Stěnový výklenek | NEW | 0.09 | 0.125 | 0.011 | 0.15 | 0.6 | NEMSOK - Object Layer Attributes #1, Označení: UT
VZT | Půdorys 1.PP | Betonářské práce | 1352SVý0798502886 | m3 | Stěnový výklenek | NEW | 0.25 | 0.125 | 0.031 | 0.25 | 1 | NEMSOK - Object Layer Attributes #1, Označení: VZT
UT | Půdorys 1.PP | Betonářské práce | 1352SVý0798501507 | m3 | Stěnový výklenek | NEW | 0.045 | 0.125 | 0.006 | 0.15 | 0.3 | NEMSOK - Object Layer Attributes #1, Označení: UT
UT | Půdorys 1.PP | Betonářské práce | 1352SVý0798501513 | m2 | Stěnový výklenek | NEW | 0.045 | 0.1 | 0.005 | 0.15 | 0.3 | NEMSOK - Object Layer Attributes #1, Označení: UT
Okenní otvor | Půdorys 1.PP | Zateplovací systémy | 1352Okn0798502474 | m2 | Okenní otvor | NEW | 1.575 | 0.1 | 0.158 | 1.75 | 0.9
Prostup deskou | Půdorys 1.PP | Betonářské práce | 1354DOt0000001106 | m3 | Otvor v desce | NEW | 0.15 | 0.5 | 0.038 | 0.25 | 0.3
Prostup deskou | Půdorys 1.PP | Betonářské práce | 1354DOt0000000744 | m3 | Otvor v desce | NEW | 0.81 | 2.7 | 0.203 | 0.25 | 0.3
Prostup deskou | Půdorys 1.PP | Betonářské práce | 1354DOt0000000245 | m3 | Otvor v desce | NEW | 0.26 | 0.4 | 0.065 | 0.25 | 0.65
Prostup deskou | Půdorys 1.PP | Betonářské práce | 1354DOt0000000263 | m3 | Otvor v desce | NEW | 0.18 | 0.45 | 0.045 | 0.25 | 0.4
Prostup deskou | Půdorys 1.PP | Betonářské práce | 1354DOt0000000265 | m3 | Otvor v desce | NEW | 0.18 | 0.45 | 0.045 | 0.25 | 0.4
Prostup deskou | Půdorys 1.PP | Betonářské práce | 1354DOt0000001982 | m3 | Otvor v desce | NEW | 0.065 | 0.1 | 0.016 | 0.25 | 0.65
Prostup deskou | Půdorys 1.PP | Betonářské práce | 1354DOt0000002156 | m3 | Otvor v desce | NEW | 0.07 | 0.2 | 0.007 | 0.1 | 0.35
Prostup deskou | Půdorys 1.PP | Betonářské práce | 1354DOt0000002129 | m3 | Otvor v desce | NEW | 0.27 | 0.9 | 0.027 | 0.1 | 0.3
Prostup deskou | Půdorys 1.PP | Betonářské práce | 1354DOt0000002179 | m3 | Otvor v desce | NEW | 0.01 | 0.1 | 0.001 | 0.1 | 0.1
Prostup deskou | Půdorys 1.PP | Betonářské práce | 1354DOt0000001089 | m3 | Otvor v desce | NEW | 0.3 | 0.6 | 0.075 | 0.25 | 0.5
Prostup deskou | Půdorys 1.PP | Betonářské práce | 1354DOt0000002067 | m3 | Otvor v desce | NEW | 0.21 | 0.6 | 0.052 | 0.25 | 0.35
Prostup deskou | Půdorys 1.PP | Betonářské práce | 1354DOt0000002333 | m3 | Otvor v desce | NEW | 0.27 | 0.3 | 0.067 | 0.25 | 0.9
Prostup deskou | Půdorys 1.PP | Betonářské práce | 1354DOt0000000247 | m3 | Otvor v desce | NEW | 0.1 | 0.4 | 0.025 | 0.25 | 0.25
Prostup deskou | Půdorys 1.PP | Betonářské práce | 1354DOt0000002198 | m3 | Otvor v desce | NEW | 0.09 | 0.3 | 0.023 | 0.25 | 0.3
Prostup deskou | Půdorys 1.PP | Betonářské práce | 1354DOt0000000241 | m3 | Otvor v desce | NEW | 0.44 | 1.1 | 0.11 | 0.25 | 0.4
Prostup deskou | Půdorys 1.PP | Betonářské práce | 1354DOt0000000237 | m3 | Otvor v desce | NEW | 0.4 | 1 | 0.1 | 0.25 | 0.4
Prostup deskou | Půdorys 1.PP | Betonářské práce | 1354DOt0000000254 | m3 | Otvor v desce | NEW | 0.3 | 0.5 | 0.075 | 0.25 | 0.6
Prostup deskou | Půdorys 1.PP | Betonářské práce | 1354DOt0000000230 | m3 | Otvor v desce | NEW | 0.249 | 0.83 | 0.062 | 0.25 | 0.3
Prostup deskou | Půdorys 1.PP | Betonářské práce | 1354DOt0000000226 | m3 | Otvor v desce | NEW | 0.18 | 0.3 | 0.045 | 0.25 | 0.6
Prostup deskou | Půdorys 1.PP | Betonářské práce | 1354DOt0000002399 | m3 | Otvor v desce | NEW | 0.018 | 0.118 | 0.004 | 0.25 | 0.15
Prostup deskou | Půdorys 1.PP | Betonářské práce | 1354DOt0000002404 | m3 | Otvor v desce | NEW | 0.018 | 0.118 | 0.004 | 0.25 | 0.15
Prostup deskou | Půdorys 1.PP | Betonářské práce | 1354DOt0000002409 | m3 | Otvor v desce | NEW | 0.018 | 0.118 | 0.004 | 0.25 | 0.15
Prostup deskou | Půdorys 1.PP | Betonářské práce | 1354DOt0000002414 | m3 | Otvor v desce | NEW | 0.018 | 0.118 | 0.004 | 0.25 | 0.15
Prostup deskou | Půdorys 1.PP | Betonářské práce | 1354DOt0000002507 | m3 | Otvor v desce | NEW | 0.06 | 0.4 | 0.015 | 0.25 | 0.15
Prostup deskou | Půdorys 1.PP | Betonářské práce | 1354DOt0000002512 | m3 | Otvor v desce | NEW | 0.018 | 0.118 | 0.004 | 0.25 | 0.15
Prostup deskou | Půdorys 1.PP | Betonářské práce | 1354DOt0000002517 | m3 | Otvor v desce | NEW | 0.018 | 0.118 | 0.004 | 0.25 | 0.15
Prostup deskou | Půdorys 1.PP | Betonářské práce | 1354DOt0000002522 | m3 | Otvor v desce | NEW | 0.008 | 0.079 | 0.002 | 0.25 | 0.1
Prostup deskou | Půdorys 1.PP | Betonářské práce | 1354DOt0000000822 | m3 | Otvor v desce | NEW | 0.22 | 0.4 | 0.055 | 0.25 | 0.55
Prostup deskou | Půdorys 1.PP | Betonářské práce | 1354DOt0000000847 | m3 | Otvor v desce | NEW | 0.25 | 0.5 | 0.062 | 0.25 | 0.5
Prostup deskou | Půdorys 1.PP | Betonářské práce | 1354DOt0000000887 | m3 | Otvor v desce | NEW | 0.24 | 0.4 | 0.06 | 0.25 | 0.6
Prostup deskou | Půdorys 1.PP | Betonářské práce | 1354DOt0000000860 | m3 | Otvor v desce | NEW | 0.16 | 0.4 | 0.04 | 0.25 | 0.4
Prostup deskou | Půdorys 1.PP | Betonářské práce | 1354DOt0000002527 | m3 | Otvor v desce | NEW | 0.008 | 0.079 | 0.002 | 0.25 | 0.1
Prostup deskou | Půdorys 1.PP | Betonářské práce | 1354DOt0000002532 | m3 | Otvor v desce | NEW | 0.018 | 0.118 | 0.004 | 0.25 | 0.15
Prostup deskou | Půdorys 1.PP | Betonářské práce | 1354DOt0000002419 | m3 | Otvor v desce | NEW | 0.018 | 0.118 | 0.004 | 0.25 | 0.15
Prostup deskou | Půdorys 1.PP | Betonářské práce | 1354DOt0000002542 | m3 | Otvor v desce | NEW | 0.008 | 0.079 | 0.002 | 0.25 | 0.1
Prostup deskou | Půdorys 1.PP | Betonářské práce | 1354DOt0000001047 | m3 | Otvor v desce | NEW | 0.14 | 0.7 | 0.035 | 0.25 | 0.2
Prostup deskou | Půdorys 1.PP | Betonářské práce | 1354DOt0000001034 | m3 | Otvor v desce | NEW | 0.385 | 0.7 | 0.096 | 0.25 | 0.55
Prostup deskou | Půdorys 1.PP | Betonářské práce | 1354DOt0000000955 | m3 | Otvor v desce | NEW | 0.21 | 1.05 | 0.053 | 0.25 | 0.2
Prostup deskou | Půdorys 1.PP | Betonářské práce | 1354DOt0000000938 | m3 | Otvor v desce | NEW | 2.992 | 1.05 | 0.748 | 0.25 | 2.85
Prostup deskou | Půdorys 1.PP | Betonářské práce | 1354DOt0000002537 | m3 | Otvor v desce | NEW | 0.018 | 0.118 | 0.004 | 0.25 | 0.15
Prostup deskou | Půdorys 1.PP | Betonářské práce | 1354DOt0000002547 | m3 | Otvor v desce | NEW | 0.008 | 0.079 | 0.002 | 0.25 | 0.1
Prostup deskou | Půdorys 1.PP | Betonářské práce | 1354DOt0000000892 | m3 | Otvor v desce | NEW | 0.332 | 0.7 | 0.083 | 0.25 | 0.475
Prostup deskou | Půdorys 1.PP | Betonářské práce | 1354DOt0000001151 | m3 | Otvor v desce | NEW | 0.6 | 1 | 0.15 | 0.25 | 0.6
Prostup deskou | Půdorys 1.PP | Betonářské práce | 1354DOt0000001162 | m3 | Otvor v desce | NEW | 0.3 | 0.5 | 0.075 | 0.25 | 0.6
Prostup deskou | Půdorys 1.PP | Betonářské práce | 1354DOt0000002552 | m3 | Otvor v desce | NEW | 0.008 | 0.079 | 0.002 | 0.25 | 0.1
Prostup deskou | Půdorys 1.PP | Betonářské práce | 1354DOt0000002557 | m3 | Otvor v desce | NEW | 0.018 | 0.118 | 0.005 | 0.3 | 0.15
Prostup deskou | Půdorys 1.PP | Betonářské práce | 1354DOt0000002562 | m3 | Otvor v desce | NEW | 0.018 | 0.118 | 0.005 | 0.3 | 0.15
Prostup deskou | Půdorys 1.PP | Betonářské práce | 1354DOt0000000783 | m3 | Otvor v desce | NEW | 0.237 | 0.5 | 0.059 | 0.25 | 0.475
Prostup deskou | Půdorys 1.PP | Betonářské práce | 1354DOt0000000792 | m3 | Otvor v desce | NEW | 0.25 | 0.5 | 0.062 | 0.25 | 0.5
Prostup deskou | Půdorys 1.PP | Betonářské práce | 1354DOt0000002498 | m3 | Otvor v desce | NEW | 0.079 | 0.525 | 0.02 | 0.25 | 0.15
UT+VZT | Půdorys 1.PP | Betonářské práce | 1364SVý0798583941 | m3 | Stěnový výklenek | NEW | 0.27 | 0.05 | 0.014 | 0.25 | 1.08 | NEMSOK - Object Layer Attributes #1, Označení: UT+VZT
Dveřní otvor | Půdorys 1.PP | Betonářské práce | 1364Dve0798523495 | m3 | Dveřní otvor | NEW | 2.424 | 0.05 | 0.121 | 2.02 | 1.2 | NEMSOK - Object Layer Attributes #1, Směr otevírání dveří: -; Object Layer Attributes #1, Označení: Dveřní otvor
Prostup stěnou | Půdorys 1.PP | Betonářské práce | 1364SVý0798562884 | m3 | Stěnový výklenek | NEW | 0.09 | 0.05 | 0.004 | 0.15 | 0.6 | NEMSOK - Object Layer Attributes #1, Označení: Prostup stěnou
Dveřní otvor | Půdorys 1.PP | Betonářské práce | 1364Dve0798523475 | m3 | Dveřní otvor | NEW | 2.167 | 0.05 | 0.108 | 1.97 | 1.1 | NEMSOK - Object Layer Attributes #1, Směr otevírání dveří: -; Object Layer Attributes #1, Označení: Dveřní otvor
UT | Půdorys 1.PP | Betonářské práce | 1364SVý0798583920 | m3 | Stěnový výklenek | NEW | 0.045 | 0.05 | 0.002 | 0.15 | 0.3 | NEMSOK - Object Layer Attributes #1, Označení: UT
Prostup stěnou | Půdorys 1.PP | Betonářské práce | 1364SVý0798562435 | m3 | Stěnový výklenek | NEW | 0.049 | 0.05 | 0.002 | 0.25 | 0.25 | NEMSOK - Object Layer Attributes #1, Označení: Prostup stěnou
UT | Půdorys 1.PP | Betonářské práce | 1364SVý0798592245 | m3 | Stěnový výklenek | NEW | 0.03 | 0.05 | 0.002 | 0.12 | 0.25 | NEMSOK - Object Layer Attributes #1, Označení: UT; Object Layer Attributes #1, Kód prvku: SN07.02.0001; Object Layer Attributes #1, Podlaží: 1.PP
Dveřní otvor | Půdorys 1.PP | Betonářské práce | 1364Dve0798525845 | m3 | Dveřní otvor | NEW | 2.12 | 0.05 | 0.106 | 2.12 | 1 | NEMSOK - Object Layer Attributes #1, Směr otevírání dveří: -; Object Layer Attributes #1, Označení: Dveřní otvor
Prostup stěnou | Půdorys 1.PP | Betonářské práce | 1364SVý0798562911 | m3 | Stěnový výklenek | NEW | 0.04 | 0.05 | 0.002 | 0.225 | 0.225 | NEMSOK - Object Layer Attributes #1, Označení: Prostup stěnou
Prostup stěnou | Půdorys 1.PP | Betonářské práce | 1364SVý0798562954 | m3 | Stěnový výklenek | NEW | 0.045 | 0.05 | 0.002 | 0.15 | 0.3 | NEMSOK - Object Layer Attributes #1, Označení: Prostup stěnou
Prostup stěnou | Půdorys 1.PP | Betonářské práce | 1364SVý0798592072 | m3 | Stěnový výklenek | NEW | 0.03 | 0.05 | 0.002 | 0.12 | 0.25 | NEMSOK - Object Layer Attributes #1, Kód prvku: SN07.02.0001; Object Layer Attributes #1, Podlaží: 1.PP
Dveřní otvor | Půdorys 1.PP | Betonářské práce | 1364Dve0798525667 | m3 | Dveřní otvor | NEW | 2.88 | 0.05 | 0.144 | 2.4 | 1.2 | NEMSOK - Object Layer Attributes #1, Směr otevírání dveří: -; Object Layer Attributes #1, Označení: Dveřní otvor
Prostup stěnou | Půdorys 1.PP | Betonářské práce | 1364SVý0798583632 | m3 | Stěnový výklenek | NEW | 0.008 | 0.05 | 0 | 0.1 | 0.1 | NEMSOK - Object Layer Attributes #1, Označení: Prostup stěnou
Prostup stěnou | Půdorys 1.PP | Betonářské práce | 1364SVý0798583665 | m3 | Stěnový výklenek | NEW | 0.071 | 0.05 | 0.004 | 0.3 | 0.3 | NEMSOK - Object Layer Attributes #1, Označení: Prostup stěnou
Dveřní otvor | Půdorys 1.PP | Betonářské práce | 1364Dve0798525632 | m3 | Dveřní otvor | NEW | 3.838 | 0.05 | 0.192 | 2.02 | 1.9 | NEMSOK - Object Layer Attributes #1, Směr otevírání dveří: -; Object Layer Attributes #1, Označení: Dveřní otvor
Prostup stěnou | Půdorys 1.PP | Betonářské práce | 1364SVý0798562569 | m3 | Stěnový výklenek | NEW | 0.431 | 0.05 | 0.022 | 0.325 | 1.325 | NEMSOK - Object Layer Attributes #1, Označení: Prostup stěnou
Prostup stěnou | Půdorys 1.PP | Betonářské práce | 1364SVý0798583803 | m3 | Stěnový výklenek | NEW | 0.04 | 0.05 | 0.002 | 0.225 | 0.225 | NEMSOK - Object Layer Attributes #1, Označení: Prostup stěnou
Prostup stěnou | Půdorys 1.PP | Betonářské práce | 1364SVý0798562401 | m3 | Stěnový výklenek | NEW | 0.04 | 0.05 | 0.002 | 0.225 | 0.225 | NEMSOK - Object Layer Attributes #1, Označení: Prostup stěnou
Prostup stěnou | Půdorys 1.PP | Betonářské práce | 1364SVý0798562611 | m3 | Stěnový výklenek | NEW | 0.04 | 0.05 | 0.002 | 0.225 | 0.225 | NEMSOK - Object Layer Attributes #1, Označení: Prostup stěnou
Prostup stěnou | Půdorys 1.PP | Betonářské práce | 1364SVý0798562298 | m3 | Stěnový výklenek | NEW | 0.04 | 0.05 | 0.002 | 0.225 | 0.225 | NEMSOK - Object Layer Attributes #1, Označení: Prostup stěnou
Prostup stěnou | Půdorys 1.PP | Betonářské práce | 1364SVý0798561656 | m3 | Stěnový výklenek | NEW | 0.7 | 0.05 | 0.035 | 0.7 | 1 | NEMSOK - Object Layer Attributes #1, Označení: Prostup stěnou
Prostup stěnou | Půdorys 1.PP | Betonářské práce | 1364SVý0798583732 | m3 | Stěnový výklenek | NEW | 0.071 | 0.05 | 0.004 | 0.3 | 0.3 | NEMSOK - Object Layer Attributes #1, Označení: Prostup stěnou
Prostup stěnou | Půdorys 1.PP | Betonářské práce | 1364SVý0798583566 | m3 | Stěnový výklenek | NEW | 0.008 | 0.05 | 0 | 0.1 | 0.1 | NEMSOK - Object Layer Attributes #1, Označení: Prostup stěnou
Prostup stěnou | Půdorys 1.PP | Betonářské práce | 1364SVý0798562853 | m3 | Stěnový výklenek | NEW | 0.045 | 0.05 | 0.002 | 0.15 | 0.3 | NEMSOK - Object Layer Attributes #1, Označení: Prostup stěnou
Prostup stěnou | Půdorys 1.PP | Betonářské práce | 1364SVý0798562700 | m3 | Stěnový výklenek | NEW | 0.047 | 0.05 | 0.002 | 0.15 | 0.31 | NEMSOK - Object Layer Attributes #1, Označení: Prostup stěnou
Dveřní otvor | Půdorys 1.PP | Betonářské práce | 1364Dve0798525208 | m3 | Dveřní otvor | NEW | 2.76 | 0.05 | 0.138 | 2.4 | 1.15 | NEMSOK - Object Layer Attributes #1, Směr otevírání dveří: -; Object Layer Attributes #1, Označení: Dveřní otvor
Okenní otvor | Půdorys 1.PP | Zateplovací systémy | 1364Okn0798520343 | m3 | Okenní otvor |  | 1.8 | 0.2 | 0.36 | 1.2 | 1.5 | NEMSOK - Object Layer Attributes #1, Označení: Okenní otvor; Object Layer Attributes #1, Způsob spojení vrstev: Lepený
Okenní otvor | Půdorys 1.PP | Zateplovací systémy | 1364Okn0798520766 | m3 | Okenní otvor | NEW | 1.8 | 0.2 | 0.36 | 1.2 | 1.5 | NEMSOK - Object Layer Attributes #1, Označení: Okenní otvor; Object Layer Attributes #1, Způsob spojení vrstev: Lepený
Okenní otvor | Půdorys 1.PP | Zateplovací systémy | 1364Okn0798521064 | m3 | Okenní otvor | NEW | 1.8 | 0.2 | 0.36 | 1.2 | 1.5 | NEMSOK - Object Layer Attributes #1, Označení: Okenní otvor; Object Layer Attributes #1, Způsob spojení vrstev: Lepený
Okenní otvor | Půdorys 1.PP | Zateplovací systémy | 1364Okn0798493603 | m3 | Okenní otvor |  | 1.35 | 0.2 | 0.27 | 1.5 | 0.9 | NEMSOK - Object Layer Attributes #1, Označení: Okenní otvor; Object Layer Attributes #1, Způsob spojení vrstev: Lepený
Okenní otvor | Půdorys 1.PP | Zateplovací systémy | 1364Okn0798508503 | m3 | Okenní otvor |  | 1.35 | 0.2 | 0.27 | 1.5 | 0.9 | NEMSOK - Object Layer Attributes #1, Označení: Okenní otvor; Object Layer Attributes #1, Způsob spojení vrstev: Lepený
ZTI | Půdorys 1.PP | Betonářské práce | 1364SVý0798562417 | m3 | Stěnový výklenek | NEW | 0.049 | 0.22 | 0.011 | 0.25 | 0.25 | NEMSOK - Object Layer Attributes #1, Označení: ZTI; Object Layer Attributes #1, Způsob spojení vrstev: Lepený
UT | Půdorys 1.PP | Betonářské práce | 1364SVý0798562782 | m3 | Stěnový výklenek | NEW | 0.047 | 0.17 | 0.008 | 0.15 | 0.31 | NEMSOK - Object Layer Attributes #1, Označení: UT; Object Layer Attributes #1, Způsob spojení vrstev: Lepený
UT | Půdorys 1.PP | Betonářské práce | 1364SVý0798562855 | m3 | Stěnový výklenek | NEW | 0.045 | 0.17 | 0.008 | 0.15 | 0.3 | NEMSOK - Object Layer Attributes #1, Označení: UT; Object Layer Attributes #1, Způsob spojení vrstev: Lepený
VZT | Půdorys 1.PP | Betonářské práce | 1364SVý0798585415 | m3 | Stěnový výklenek | NEW | 0.25 | 0.05 | 0.013 | 0.25 | 1 | NEMSOK - Object Layer Attributes #1, Označení: VZT
Okenní otvor | Půdorys 1.PP | Zateplovací systémy | 1364Okn0798606578 | m3 | Okenní otvor | NEW | 2.25 | 0.305 | 0.45 | 1.5 | 1.5 | NEMSOK - Object Layer Attributes #2, Status: Nový; Object Layer Attributes #2, Práce: Zateplovací systémy; Object Layer Attributes #2, Allright_Stavebni_dil_ID: 1364Okn0798606577; Object Layer Attributes #2, Jednotka: m3; Object Layer Attributes #2, Název_objektu: Okenní otvor; Object Layer Attributes #1, Označení: Okenní otvor; Object Layer Attributes #3, Status: Nový; Object Layer Attributes #3, Práce: Zateplovací systémy; Object Layer Attributes #3, Allright_Stavebni_dil_ID: 1364Okn0798606576; Object Layer Attributes #3, Jednotka: m3; Object Layer Attributes #3, Název_objektu: Okenní otvor; Object Layer Attributes #2, Označení: Okenní otvor; Object Layer Attributes #3, Označení: Okenní otvor
Okenní otvor | Půdorys 1.PP | Zateplovací systémy | 1364Okn0798606795 | m3 | Okenní otvor | DEMOLISH | 2.25 | 0.305 | 0.45 | 1.5 | 1.5 | NEMSOK - Object Layer Attributes #2, Status: Bouraný; Object Layer Attributes #2, Práce: Zateplovací systémy; Object Layer Attributes #2, Allright_Stavebni_dil_ID: 1364Okn0798606794; Object Layer Attributes #2, Jednotka: m3; Object Layer Attributes #2, Název_objektu: Okenní otvor; Object Layer Attributes #1, Označení: Okenní otvor; Object Layer Attributes #3, Status: Bouraný; Object Layer Attributes #3, Práce: Zateplovací systémy; Object Layer Attributes #3, Allright_Stavebni_dil_ID: 1364Okn0798606796; Object Layer Attributes #3, Jednotka: m3; Object Layer Attributes #3, Název_objektu: Okenní otvor; Object Layer Attributes #2, Označení: Okenní otvor; Object Layer Attributes #3, Označení: Okenní otvor
Okenní otvor | Půdorys 1.PP | Zateplovací systémy | 1364Okn0798606761 | m3 | Okenní otvor | DEMOLISH | 2.25 | 0.305 | 0.45 | 1.5 | 1.5 | NEMSOK - Object Layer Attributes #2, Status: Bouraný; Object Layer Attributes #2, Práce: Zateplovací systémy; Object Layer Attributes #2, Allright_Stavebni_dil_ID: 1364Okn0798606760; Object Layer Attributes #2, Jednotka: m3; Object Layer Attributes #2, Název_objektu: Okenní otvor; Object Layer Attributes #1, Označení: Okenní otvor; Object Layer Attributes #3, Status: Bouraný; Object Layer Attributes #3, Práce: Zateplovací systémy; Object Layer Attributes #3, Allright_Stavebni_dil_ID: 1364Okn0798606762; Object Layer Attributes #3, Jednotka: m3; Object Layer Attributes #3, Název_objektu: Okenní otvor; Object Layer Attributes #2, Označení: Okenní otvor; Object Layer Attributes #3, Označení: Okenní otvor
Okenní otvor | Půdorys 1.PP | Zateplovací systémy | 1364Okn0798606728 | m3 | Okenní otvor | DEMOLISH | 2.25 | 0.305 | 0.45 | 1.5 | 1.5 | NEMSOK - Object Layer Attributes #2, Status: Bouraný; Object Layer Attributes #2, Práce: Zateplovací systémy; Object Layer Attributes #2, Allright_Stavebni_dil_ID: 1364Okn0798606727; Object Layer Attributes #2, Jednotka: m3; Object Layer Attributes #2, Název_objektu: Okenní otvor; Object Layer Attributes #1, Označení: Okenní otvor; Object Layer Attributes #3, Status: Bouraný; Object Layer Attributes #3, Práce: Zateplovací systémy; Object Layer Attributes #3, Allright_Stavebni_dil_ID: 1364Okn0798606726; Object Layer Attributes #3, Jednotka: m3; Object Layer Attributes #3, Název_objektu: Okenní otvor; Object Layer Attributes #2, Označení: Okenní otvor; Object Layer Attributes #3, Označení: Okenní otvor
Okenní otvor | Půdorys 1.PP | Zateplovací systémy | 1364Okn0798606951 | m3 | Okenní otvor | DEMOLISH | 2.25 | 0.305 | 0.45 | 1.5 | 1.5 | NEMSOK - Object Layer Attributes #2, Status: Bouraný; Object Layer Attributes #2, Práce: Zateplovací systémy; Object Layer Attributes #2, Allright_Stavebni_dil_ID: 1364Okn0798606950; Object Layer Attributes #2, Jednotka: m3; Object Layer Attributes #2, Název_objektu: Okenní otvor; Object Layer Attributes #1, Označení: Okenní otvor; Object Layer Attributes #3, Status: Bouraný; Object Layer Attributes #3, Práce: Zateplovací systémy; Object Layer Attributes #3, Allright_Stavebni_dil_ID: 1364Okn0798606952; Object Layer Attributes #3, Jednotka: m3; Object Layer Attributes #3, Název_objektu: Okenní otvor; Object Layer Attributes #2, Označení: Okenní otvor; Object Layer Attributes #3, Označení: Okenní otvor
ZTI | Půdorys 1.PP | Suché stavební práce | 1364SVý0798591910 | m3 | Stěna | NEW | 0.045 | 0.15 | 0.007 | 0.3 | 0.15 | NEMSOK - Object Layer Attributes #1, Označení: ZTI; Object Layer Attributes #1, Podlaží: 1.NP; Object Layer Attributes #1, 2D interakce: yes; Object Layer Attributes #1, Staticky nosná konstrukce: no; Object Layer Attributes #1, Požární odolnost: EI 60; Object Layer Attributes #1, Statická funkce: Ne
ZTI | Půdorys 1.PP | Betonářské práce | 1364SVý0798583456 | m3 | Stěnový výklenek | NEW | 0.031 | 0.5 | 0.016 | 0.2 | 0.2 | NEMSOK - Object Layer Attributes #1, Označení: ZTI
RAD | Půdorys 1.PP | Betonářské práce | 1364SVý0798585741 | m3 | Stěnový výklenek | NEW | 0.031 | 0.5 | 0.016 | 0.2 | 0.2 | NEMSOK - Object Layer Attributes #1, Označení: RAD
RAD | Půdorys 1.PP | Betonářské práce | 1364SVý0798585735 | m3 | Stěnový výklenek | NEW | 0.031 | 0.5 | 0.016 | 0.2 | 0.2 | NEMSOK - Object Layer Attributes #1, Označení: RAD
ZTI | Půdorys 1.PP | Betonářské práce | 1364SVý0798585972 | m3 | Stěnový výklenek | NEW | 0.031 | 0.5 | 0.016 | 0.2 | 0.2 | NEMSOK - Object Layer Attributes #1, Označení: ZTI
ZTI | Půdorys 1.PP | Betonářské práce | 1364SVý0798585994 | m3 | Stěnový výklenek | NEW | 0.031 | 0.5 | 0.016 | 0.2 | 0.2 | NEMSOK - Object Layer Attributes #1, Označení: ZTI
Prostup stěnou | Půdorys 1.PP | Suché stavební práce | 1364SVý0798591943 | m3 | Stěna | NEW | 0.045 | 0.15 | 0.007 | 0.3 | 0.15 | NEMSOK - Object Layer Attributes #1, Označení: Prostup stěnou; Object Layer Attributes #1, Podlaží: 1.NP; Object Layer Attributes #1, 2D interakce: yes; Object Layer Attributes #1, Staticky nosná konstrukce: no; Object Layer Attributes #1, Požární odolnost: EI 60; Object Layer Attributes #1, Statická funkce: Ne
Prostup stěnou | Půdorys 1.PP | Suché stavební práce | 1364SVý0798591937 | m3 | Stěna | NEW | 0.045 | 0.15 | 0.007 | 0.3 | 0.15 | NEMSOK - Object Layer Attributes #1, Označení: Prostup stěnou; Object Layer Attributes #1, Podlaží: 1.NP; Object Layer Attributes #1, 2D interakce: yes; Object Layer Attributes #1, Staticky nosná konstrukce: no; Object Layer Attributes #1, Požární odolnost: EI 60; Object Layer Attributes #1, Statická funkce: Ne
RAD | Půdorys 1.PP | Betonářské práce | 1364SVý0798585729 | m3 | Stěnový výklenek | NEW | 0.031 | 0.5 | 0.016 | 0.2 | 0.2 | NEMSOK - Object Layer Attributes #1, Označení: RAD
ZTI | Půdorys 1.PP | Betonářské práce | 1364SVý0798586013 | m3 | Stěnový výklenek | NEW | 0.031 | 0.5 | 0.016 | 0.2 | 0.2 | NEMSOK - Object Layer Attributes #1, Označení: ZTI
RAD | Půdorys 1.PP | Betonářské práce | 1364SVý0798585708 | m3 | Stěnový výklenek | NEW | 0.031 | 0.5 | 0.016 | 0.2 | 0.2 | NEMSOK - Object Layer Attributes #1, Označení: RAD
RAD | Půdorys 1.PP | Betonářské práce | 1364SVý0798585900 | m3 | Stěnový výklenek | NEW | 0.031 | 0.5 | 0.016 | 0.2 | 0.2 | NEMSOK - Object Layer Attributes #1, Označení: RAD
RAD | Půdorys 1.PP | Betonářské práce | 1364SVý0798585912 | m3 | Stěnový výklenek | NEW | 0.031 | 0.5 | 0.016 | 0.2 | 0.2 | NEMSOK - Object Layer Attributes #1, Označení: RAD
RAD | Půdorys 1.PP | Betonářské práce | 1364SVý0798585617 | m3 | Stěnový výklenek | NEW | 0.031 | 0.5 | 0.016 | 0.2 | 0.2 | NEMSOK - Object Layer Attributes #1, Označení: RAD
ZTI | Půdorys 1.PP | Betonářské práce | 1364SVý0798587203 | m3 | Stěnový výklenek | NEW | 0.049 | 0.5 | 0.024 | 0.25 | 0.25 | NEMSOK - Object Layer Attributes #1, Označení: ZTI
ZTI | Půdorys 1.PP | Betonářské práce | 1364SVý0798583468 | m3 | Stěnový výklenek | NEW | 0.031 | 0.5 | 0.016 | 0.2 | 0.2 | NEMSOK - Object Layer Attributes #1, Označení: ZTI
RAD | Půdorys 1.PP | Betonářské práce | 1364SVý0798585751 | m3 | Stěnový výklenek | NEW | 0.031 | 0.5 | 0.016 | 0.2 | 0.2 | NEMSOK - Object Layer Attributes #1, Označení: RAD
Dveřní otvor | Půdorys 1.PP | Betonářské práce | 1364Dve0000006683 | m3 | Dveřní otvor | NEW | 2.05 | 0.2 | 0.41 | 2.05 | 1 | NEMSOK - Object Layer Attributes #1, Směr otevírání dveří: P; Object Layer Attributes #1, Označení: Dveřní otvor; Object Layer Attributes #1, Podlaží: 1.PP
Dveřní otvor | Půdorys 1.PP | Betonářské práce | 1364Dve0000010602 | m3 | Dveřní otvor | EXISTING | 1.52 | 0.032 | 0.049 | 2 | 0.76 | NEMSOK - Object Layer Attributes #1, Směr otevírání dveří: P; Object Layer Attributes #1, Označení: Dveřní otvor
Dveřní otvor | Půdorys 1.PP | Betonářské práce | 1364Dve0798473673 | m3 | Dveřní otvor | NEW | 2.12 | 0.1 | 0.212 | 2.12 | 1 | NEMSOK - Object Layer Attributes #1, Směr otevírání dveří: P; Object Layer Attributes #1, Označení: Dveřní otvor; Object Layer Attributes #1, Podlaží: 1.PP
Stěnová nika | Půdorys 1.PP | Zednické práce | 1364SNi0798522127 | m3 | Stěnová nika | NEW | 0.423 | 0.175 | 0.074 | 0.65 | 0.65 | NEMSOK - Object Layer Attributes #1, Označení: Stěnová nika
VZT | Půdorys 1.PP | Betonářské práce | 1364SVý0798585380 | m3 | Stěnový výklenek | NEW | 0.035 | 0.25 | 0.009 | 0.21 | 0.21 | NEMSOK - Object Layer Attributes #1, Označení: VZT
Dveřní otvor | Půdorys 1.PP | Betonářské práce | 1364Dve0798526748 | m3 | Dveřní otvor | NEW | 3.24 | 0.25 | 0.81 | 2.7 | 1.2 | NEMSOK - Object Layer Attributes #1, Směr otevírání dveří: -; Object Layer Attributes #1, Označení: Dveřní otvor; Object Layer Attributes #1, Třída pevnosti ocele: B500B; Object Layer Attributes #1, Stupeň vyztužení: 150; Object Layer Attributes #1, U-hodnota: 3.23; Object Layer Attributes #1, Třída pevnosti betonu: C25/30-XC1; Object Layer Attributes #1, Krytí výztuže: 25mm
Dveřní otvor | Půdorys 1.PP | Betonářské práce | 1364Dve0798526781 | m3 | Dveřní otvor | NEW | 3.24 | 0.25 | 0.81 | 2.7 | 1.2 | NEMSOK - Object Layer Attributes #1, Směr otevírání dveří: -; Object Layer Attributes #1, Označení: Dveřní otvor; Object Layer Attributes #1, Třída pevnosti ocele: B500B; Object Layer Attributes #1, Stupeň vyztužení: 150; Object Layer Attributes #1, U-hodnota: 3.23; Object Layer Attributes #1, Třída pevnosti betonu: C25/30-XC1; Object Layer Attributes #1, Krytí výztuže: 25mm
UT | Půdorys 1.PP | Betonářské práce | 1364SVý0798562732 | m3 | Stěnový výklenek | NEW | 0.046 | 0.25 | 0.012 | 0.15 | 0.31 | NEMSOK - Object Layer Attributes #1, Označení: UT; Object Layer Attributes #1, Třída pevnosti ocele: B500B; Object Layer Attributes #1, Stupeň vyztužení: 150; Object Layer Attributes #1, U-hodnota: 3.23; Object Layer Attributes #1, Třída pevnosti betonu: C25/30-XC1; Object Layer Attributes #1, Krytí výztuže: 25mm
UT | Půdorys 1.PP | Betonářské práce | 1364SVý0798562856 | m3 | Stěnový výklenek | NEW | 0.045 | 0.25 | 0.011 | 0.15 | 0.3 | NEMSOK - Object Layer Attributes #1, Označení: UT; Object Layer Attributes #1, Třída pevnosti ocele: B500B; Object Layer Attributes #1, Stupeň vyztužení: 150; Object Layer Attributes #1, U-hodnota: 3.23; Object Layer Attributes #1, Třída pevnosti betonu: C25/30-XC1; Object Layer Attributes #1, Krytí výztuže: 25mm
ZTI | Půdorys 1.PP | Betonářské práce | 1364SVý0798562971 | m3 | Stěnový výklenek | NEW | 0.033 | 0.25 | 0.008 | 0.11 | 0.3 | NEMSOK - Object Layer Attributes #1, Označení: ZTI; Object Layer Attributes #1, Třída pevnosti ocele: B500B; Object Layer Attributes #1, Stupeň vyztužení: 150; Object Layer Attributes #1, U-hodnota: 3.23; Object Layer Attributes #1, Třída pevnosti betonu: C25/30-XC1; Object Layer Attributes #1, Krytí výztuže: 25mm
UT | Půdorys 1.PP | Betonářské práce | 1364SVý0798562998 | m3 | Stěnový výklenek | NEW | 0.045 | 0.25 | 0.011 | 0.15 | 0.3 | NEMSOK - Object Layer Attributes #1, Označení: UT; Object Layer Attributes #1, Třída pevnosti ocele: B500B; Object Layer Attributes #1, Stupeň vyztužení: 150; Object Layer Attributes #1, U-hodnota: 3.23; Object Layer Attributes #1, Třída pevnosti betonu: C25/30-XC1; Object Layer Attributes #1, Krytí výztuže: 25mm
ZTI | Půdorys 1.PP | Betonářské práce | 1364SVý0798583624 | m3 | Stěnový výklenek | NEW | 0.008 | 0.25 | 0.002 | 0.1 | 0.1 | NEMSOK - Object Layer Attributes #1, Označení: ZTI; Object Layer Attributes #1, Třída pevnosti ocele: B500B; Object Layer Attributes #1, Stupeň vyztužení: 150; Object Layer Attributes #1, U-hodnota: 3.23; Object Layer Attributes #1, Třída pevnosti betonu: C25/30-XC1; Object Layer Attributes #1, Krytí výztuže: 25mm
VZT | Půdorys 1.PP | Betonářské práce | 1364SVý0798583724 | m3 | Stěnový výklenek | NEW | 0.071 | 0.25 | 0.018 | 0.3 | 0.3 | NEMSOK - Object Layer Attributes #1, Označení: VZT; Object Layer Attributes #1, Třída pevnosti ocele: B500B; Object Layer Attributes #1, Stupeň vyztužení: 150; Object Layer Attributes #1, U-hodnota: 3.23; Object Layer Attributes #1, Třída pevnosti betonu: C25/30-XC1; Object Layer Attributes #1, Krytí výztuže: 25mm
VZT | Půdorys 1.PP | Betonářské práce | 1364SVý0798562268 | m3 | Stěnový výklenek | NEW | 0.04 | 0.2 | 0.008 | 0.225 | 0.225 | NEMSOK - Object Layer Attributes #1, Označení: VZT; Object Layer Attributes #1, Třída pevnosti ocele: B500B; Object Layer Attributes #1, Stupeň vyztužení: 150; Object Layer Attributes #1, U-hodnota: 3.23; Object Layer Attributes #1, Třída pevnosti betonu: C25/30-XC1; Object Layer Attributes #1, Krytí výztuže: 25mm
Okenní otvor | Půdorys 1.PP | Zateplovací systémy | 1364Okn0798495819 | m3 | Okenní otvor | NEW | 2.25 | 0.52 | 0.675 | 1.5 | 1.5 | NEMSOK - Object Layer Attributes #2, Status: Nový; Object Layer Attributes #2, Práce: Zateplovací systémy; Object Layer Attributes #2, Allright_Stavebni_dil_ID: 1364Okn0798495821; Object Layer Attributes #2, Jednotka: m3; Object Layer Attributes #2, Název_objektu: Okenní otvor; Object Layer Attributes #1, Označení: Okenní otvor; Object Layer Attributes #2, Označení: Okenní otvor; Object Layer Attributes #1, Třída pevnosti ocele: B500B; Object Layer Attributes #1, Stupeň vyztužení: 150; Object Layer Attributes #1, U-hodnota: 3.23; Object Layer Attributes #1, Třída pevnosti betonu: C25/30-XC1; Object Layer Attributes #1, Krytí výztuže: 25mm; Object Layer Attributes #2, Způsob spojení vrstev: Lepený
Okenní otvor | Půdorys 1.PP | Zateplovací systémy | 1364Okn0798495876 | m3 | Okenní otvor | NEW | 2.25 | 0.52 | 0.675 | 1.5 | 1.5 | NEMSOK - Object Layer Attributes #2, Status: Nový; Object Layer Attributes #2, Práce: Zateplovací systémy; Object Layer Attributes #2, Allright_Stavebni_dil_ID: 1364Okn0798495878; Object Layer Attributes #2, Jednotka: m3; Object Layer Attributes #2, Název_objektu: Okenní otvor; Object Layer Attributes #1, Označení: Okenní otvor; Object Layer Attributes #2, Označení: Okenní otvor; Object Layer Attributes #1, Třída pevnosti ocele: B500B; Object Layer Attributes #1, Stupeň vyztužení: 150; Object Layer Attributes #1, U-hodnota: 3.23; Object Layer Attributes #1, Třída pevnosti betonu: C25/30-XC1; Object Layer Attributes #1, Krytí výztuže: 25mm; Object Layer Attributes #2, Způsob spojení vrstev: Lepený
VZT | Půdorys 1.PP | Betonářské práce | 1364SVý0798561426 | m3 | Stěnový výklenek | NEW | 0.7 | 0.52 | 0.154 | 0.7 | 1 | NEMSOK - Object Layer Attributes #2, Status: Nový; Object Layer Attributes #2, Práce: Betonářské práce; Object Layer Attributes #2, Allright_Stavebni_dil_ID: 1364SVý0798561566; Object Layer Attributes #2, Jednotka: m3; Object Layer Attributes #2, Název_objektu: Stěnový výklenek; Object Layer Attributes #1, Označení: VZT; Object Layer Attributes #2, Označení: Prostup stěnou; Object Layer Attributes #1, Třída pevnosti ocele: B500B; Object Layer Attributes #1, Stupeň vyztužení: 150; Object Layer Attributes #1, U-hodnota: 3.23; Object Layer Attributes #1, Třída pevnosti betonu: C25/30-XC1; Object Layer Attributes #1, Krytí výztuže: 25mm; Object Layer Attributes #2, Způsob spojení vrstev: Lepený
VZT | Půdorys 1.PP | Betonářské práce | 1364SVý0798561667 | m3 | Stěnový výklenek | NEW | 0.7 | 0.52 | 0.154 | 0.7 | 1 | NEMSOK - Object Layer Attributes #2, Status: Nový; Object Layer Attributes #2, Práce: Betonářské práce; Object Layer Attributes #2, Allright_Stavebni_dil_ID: 1364SVý0798561666; Object Layer Attributes #2, Jednotka: m3; Object Layer Attributes #2, Název_objektu: Stěnový výklenek; Object Layer Attributes #1, Označení: VZT; Object Layer Attributes #2, Označení: Prostup stěnou; Object Layer Attributes #1, Třída pevnosti ocele: B500B; Object Layer Attributes #1, Stupeň vyztužení: 150; Object Layer Attributes #1, U-hodnota: 3.23; Object Layer Attributes #1, Třída pevnosti betonu: C25/30-XC1; Object Layer Attributes #1, Krytí výztuže: 25mm; Object Layer Attributes #2, Způsob spojení vrstev: Lepený
ZTI | Půdorys 1.PP | Betonářské práce | 1364SVý0798562483 | m3 | Stěnový výklenek | NEW | 0.049 | 0.3 | 0.015 | 0.25 | 0.25 | NEMSOK - Object Layer Attributes #1, Označení: ZTI; Object Layer Attributes #1, Třída pevnosti ocele: B500B; Object Layer Attributes #1, Stupeň vyztužení: 150; Object Layer Attributes #1, U-hodnota: 3.23; Object Layer Attributes #1, Třída pevnosti betonu: C25/30-XC1; Object Layer Attributes #1, Krytí výztuže: 25mm
Dveřní otvor | Půdorys 1.PP | Betonářské práce | 1364Dve0798521557 | m3 | Dveřní otvor | NEW | 2.12 | 0.125 | 0.265 | 2.12 | 1 | NEMSOK - Object Layer Attributes #1, Směr otevírání dveří: L; Object Layer Attributes #1, Označení: Dveřní otvor; Object Layer Attributes #1, Podlaží: 1.PP
Dveřní otvor | Půdorys 1.PP | Betonářské práce | 1364Dve0798521671 | m3 | Dveřní otvor | NEW | 1.696 | 0.125 | 0.212 | 2.12 | 0.8 | NEMSOK - Object Layer Attributes #1, Směr otevírání dveří: P; Object Layer Attributes #1, Označení: Dveřní otvor; Object Layer Attributes #1, Podlaží: 1.PP
VZT | Půdorys 1.PP | Betonářské práce | 1364SVý0798585438 | m3 | Stěnový výklenek | NEW | 0.049 | 0.125 | 0.006 | 0.25 | 0.25 | NEMSOK - Object Layer Attributes #1, Označení: VZT; Object Layer Attributes #1, Podlaží: 1.PP
Dveřní otvor | Půdorys 1.PP | Betonářské práce | 1364Dve0798521734 | m3 | Dveřní otvor | NEW | 2.12 | 0.125 | 0.265 | 2.12 | 1 | NEMSOK - Object Layer Attributes #1, Směr otevírání dveří: L; Object Layer Attributes #1, Označení: Dveřní otvor; Object Layer Attributes #1, Podlaží: 1.PP
Dveřní otvor | Půdorys 1.PP | Betonářské práce | 1364Dve0798521804 | m3 | Dveřní otvor | NEW | 2.12 | 0.125 | 0.265 | 2.12 | 1 | NEMSOK - Object Layer Attributes #1, Směr otevírání dveří: P; Object Layer Attributes #1, Označení: Dveřní otvor; Object Layer Attributes #1, Podlaží: 1.PP
Dveřní otvor | Půdorys 1.PP | Betonářské práce | 1364Dve0798528551 | m3 | Dveřní otvor | NEW | 1.908 | 0.125 | 0.238 | 2.12 | 0.9 | NEMSOK - Object Layer Attributes #1, Směr otevírání dveří: L; Object Layer Attributes #1, Označení: Dveřní otvor; Object Layer Attributes #1, Podlaží: 1.PP
Dveřní otvor | Půdorys 1.PP | Betonářské práce | 1364Dve0798529206 | m3 | Dveřní otvor | NEW | 2.544 | 0.125 | 0.318 | 2.12 | 1.2 | NEMSOK - Object Layer Attributes #1, Směr otevírání dveří: L; Object Layer Attributes #1, Označení: Dveřní otvor; Object Layer Attributes #1, Podlaží: 1.PP
Okenní otvor | Půdorys 1.PP | Zateplovací systémy | 1364Okn0798561850 | m3 | Okenní otvor | NEW | 2.175 | 0.1 | 0.218 | 1.45 | 1.5 | NEMSOK - Object Layer Attributes #1, Označení: Okenní otvor; Object Layer Attributes #1, Podlaží: 1.PP
Okenní otvor | Půdorys 1.PP | Zateplovací systémy | 1364Okn0798561885 | m3 | Okenní otvor | NEW | 2.175 | 0.1 | 0.218 | 1.45 | 1.5 | NEMSOK - Object Layer Attributes #1, Označení: Okenní otvor; Object Layer Attributes #1, Podlaží: 1.PP
Okenní otvor | Půdorys 1.PP | Zateplovací systémy | 1364Okn0798561903 | m3 | Okenní otvor | NEW | 2.175 | 0.1 | 0.218 | 1.45 | 1.5 | NEMSOK - Object Layer Attributes #1, Označení: Okenní otvor; Object Layer Attributes #1, Podlaží: 1.PP
Okenní otvor | Půdorys 1.PP | Zateplovací systémy | 1364Okn0798561922 | m3 | Okenní otvor | NEW | 1.575 | 0.1 | 0.158 | 1.75 | 0.9 | NEMSOK - Object Layer Attributes #1, Označení: Okenní otvor; Object Layer Attributes #1, Podlaží: 1.PP
Okenní otvor | Půdorys 1.PP | Zateplovací systémy | 1364Okn0798561942 | m3 | Okenní otvor | NEW | 1.575 | 0.1 | 0.158 | 1.75 | 0.9 | NEMSOK - Object Layer Attributes #1, Označení: Okenní otvor; Object Layer Attributes #1, Podlaží: 1.PP
Prostup stěnou | Půdorys 1.PP | Betonářské práce | 1364SVý0798584762 | m3 | Stěnový výklenek | NEW | 0.289 | 0.1 | 0.029 | 0.425 | 0.68 | NEMSOK - Object Layer Attributes #1, Označení: Prostup stěnou; Object Layer Attributes #1, Podlaží: 1.PP
Dveřní otvor | Půdorys 1.PP | Betonářské práce | 1364Dve0798605930 | m3 | Dveřní otvor | NEW | 2.12 | 0.125 | 0.265 | 2.12 | 1 | NEMSOK - Object Layer Attributes #1, Směr otevírání dveří: P; Object Layer Attributes #1, Označení: Dveřní otvor
Dveřní otvor | Půdorys 1.PP | Betonářské práce | 1364Dve0798606376 | m3 | Dveřní otvor |  | 2.424 | 0.125 | 0.303 | 2.02 | 1.2 | NEMSOK - Object Layer Attributes #1, Směr otevírání dveří: -; Object Layer Attributes #1, Označení: Dveřní otvor
Dveřní otvor | Půdorys 1.PP | Betonářské práce | 1364Dve0798606101 | m3 | Dveřní otvor | DEMOLISH | 1.818 | 0.125 | 0.227 | 2.02 | 0.9 | NEMSOK - Object Layer Attributes #1, Směr otevírání dveří: L; Object Layer Attributes #1, Označení: Dveřní otvor
Dveřní otvor | Půdorys 1.PP | Betonářské práce | 1364Dve0798606468 | m3 | Dveřní otvor | NEW | 2.424 | 0.125 | 0.303 | 2.02 | 1.2 | NEMSOK - Object Layer Attributes #1, Směr otevírání dveří: P; Object Layer Attributes #1, Označení: Dveřní otvor
Dveřní otvor | Půdorys 1.PP | Betonářské práce | 1364Dve0798606516 | m3 | Dveřní otvor |  | 1.696 | 0.125 | 0.212 | 2.12 | 0.8 | NEMSOK - Object Layer Attributes #1, Směr otevírání dveří: P; Object Layer Attributes #1, Označení: Dveřní otvor
Dveřní otvor | Půdorys 1.PP | Betonářské práce | 1364Dve0798606543 | m3 | Dveřní otvor | NEW | 2.544 | 0.125 | 0.318 | 2.12 | 1.2 | NEMSOK - Object Layer Attributes #1, Směr otevírání dveří: L; Object Layer Attributes #1, Označení: Dveřní otvor
Okenní otvor | Půdorys 1.PP | Zateplovací systémy | 1364Okn0798607213 | m3 | Okenní otvor | NEW | 1.35 | 0.305 | 0.27 | 1.5 | 0.9 | NEMSOK - Object Layer Attributes #2, Status: Nový; Object Layer Attributes #2, Práce: Zateplovací systémy; Object Layer Attributes #2, Allright_Stavebni_dil_ID: 1364Okn0798607212; Object Layer Attributes #2, Jednotka: m3; Object Layer Attributes #2, Název_objektu: Okenní otvor; Object Layer Attributes #3, Status: Nový; Object Layer Attributes #3, Práce: Zateplovací systémy; Object Layer Attributes #3, Allright_Stavebni_dil_ID: 1364Okn0798607211; Object Layer Attributes #3, Jednotka: m3; Object Layer Attributes #3, Název_objektu: Okenní otvor
Okenní otvor | Půdorys 1.PP | Zateplovací systémy | 1364Okn0798607194 | m3 | Okenní otvor | NEW | 1.35 | 0.305 | 0.27 | 1.5 | 0.9 | NEMSOK - Object Layer Attributes #2, Status: Nový; Object Layer Attributes #2, Práce: Zateplovací systémy; Object Layer Attributes #2, Allright_Stavebni_dil_ID: 1364Okn0798607193; Object Layer Attributes #2, Jednotka: m3; Object Layer Attributes #2, Název_objektu: Okenní otvor; Object Layer Attributes #3, Status: Nový; Object Layer Attributes #3, Práce: Zateplovací systémy; Object Layer Attributes #3, Allright_Stavebni_dil_ID: 1364Okn0798607192; Object Layer Attributes #3, Jednotka: m3; Object Layer Attributes #3, Název_objektu: Okenní otvor
Okenní otvor | Půdorys 1.PP | Zateplovací systémy | 1364Okn0798607232 | m3 | Okenní otvor | NEW | 1.35 | 0.305 | 0.27 | 1.5 | 0.9 | NEMSOK - Object Layer Attributes #2, Status: Nový; Object Layer Attributes #2, Práce: Zateplovací systémy; Object Layer Attributes #2, Allright_Stavebni_dil_ID: 1364Okn0798607231; Object Layer Attributes #2, Jednotka: m3; Object Layer Attributes #2, Název_objektu: Okenní otvor; Object Layer Attributes #3, Status: Nový; Object Layer Attributes #3, Práce: Zateplovací systémy; Object Layer Attributes #3, Allright_Stavebni_dil_ID: 1364Okn0798607230; Object Layer Attributes #3, Jednotka: m3; Object Layer Attributes #3, Název_objektu: Okenní otvor
Dveřní otvor | Půdorys 1.PP | Betonářské práce | 1364Dve0798609475 | m3 | Dveřní otvor | NEW | 3.286 | 0.125 | 0.411 | 2.12 | 1.55 | NEMSOK - Object Layer Attributes #1, Směr otevírání dveří: -
UT | Půdorys 1.PP | Suché stavební práce | 1364SVý0798583217 | m3 | Stěnový výklenek | NEW | 0.045 | 0.15 | 0.007 | 0.15 | 0.3 | NEMSOK - Object Layer Attributes #1, Označení: UT; Object Layer Attributes #1, Kód prvku: SN07.02.0001; Object Layer Attributes #1, Podlaží: 1.PP; Object Layer Attributes #1, Rozteč rastru: 625
VZT | Půdorys 1.PP | Suché stavební práce | 1364SVý0798584496 | m3 | Stěnový výklenek | NEW | 0.035 | 0.15 | 0.005 | 0.21 | 0.21 | NEMSOK - Object Layer Attributes #1, Označení: VZT; Object Layer Attributes #1, Kód prvku: SN07.02.0001; Object Layer Attributes #1, Podlaží: 1.PP; Object Layer Attributes #1, Rozteč rastru: 625
VZT | Půdorys 1.PP | Suché stavební práce | 1364SVý0798584506 | m3 | Stěnový výklenek | NEW | 0.035 | 0.15 | 0.005 | 0.21 | 0.21 | NEMSOK - Object Layer Attributes #1, Označení: VZT; Object Layer Attributes #1, Kód prvku: SN07.02.0001; Object Layer Attributes #1, Podlaží: 1.PP; Object Layer Attributes #1, Rozteč rastru: 625
Dveřní otvor | Půdorys 1.PP | Suché stavební práce | 1364Dve0000000151 | m3 | Dveřní otvor | NEW | 2.12 | 0.15 | 0.318 | 2.12 | 1 | NEMSOK - Object Layer Attributes #1, Směr otevírání dveří: L; Object Layer Attributes #1, Označení: Dveřní otvor; Object Layer Attributes #1, Kód prvku: SN07.02.0001; Object Layer Attributes #1, Podlaží: 1.PP
Dveřní otvor | Půdorys 1.PP | Suché stavební práce | 1364Dve0000003060 | m3 | Dveřní otvor | NEW | 2.12 | 0.15 | 0.318 | 2.12 | 1 | NEMSOK - Object Layer Attributes #1, Směr otevírání dveří: P; Object Layer Attributes #1, Označení: Dveřní otvor; Object Layer Attributes #1, Kód prvku: SN07.02.0001; Object Layer Attributes #1, Podlaží: 1.PP
Dveřní otvor | Půdorys 1.PP | Suché stavební práce | 1364Dve0000006169 | m3 | Dveřní otvor | NEW | 2.544 | 0.15 | 0.382 | 2.12 | 1.2 | NEMSOK - Object Layer Attributes #1, Směr otevírání dveří: P; Object Layer Attributes #1, Označení: Dveřní otvor; Object Layer Attributes #1, Kód prvku: SN07.02.0001; Object Layer Attributes #1, Podlaží: 1.PP
UT | Půdorys 1.PP | Suché stavební práce | 1364SVý0798563106 | m3 | Stěnový výklenek | NEW | 0.045 | 0.15 | 0.007 | 0.15 | 0.3 | NEMSOK - Object Layer Attributes #1, Označení: UT; Object Layer Attributes #1, Kód prvku: SN07.02.0001; Object Layer Attributes #1, Podlaží: 1.PP; Object Layer Attributes #1, Rozteč rastru: 625
VZT | Půdorys 1.PP | Suché stavební práce | 1364SVý0798584257 | m3 | Stěnový výklenek | NEW | 0.075 | 0.15 | 0.011 | 0.25 | 0.3 | NEMSOK - Object Layer Attributes #1, Označení: VZT; Object Layer Attributes #1, Kód prvku: SN07.02.0001; Object Layer Attributes #1, Podlaží: 1.PP; Object Layer Attributes #1, Rozteč rastru: 625
VZT | Půdorys 1.PP | Suché stavební práce | 1364SVý0798585183 | m3 | Stěnový výklenek | NEW | 0.035 | 0.15 | 0.005 | 0.21 | 0.21 | NEMSOK - Object Layer Attributes #1, Označení: VZT; Object Layer Attributes #1, Kód prvku: SN07.02.0001; Object Layer Attributes #1, Podlaží: 1.PP; Object Layer Attributes #1, Rozteč rastru: 625
Dveřní otvor | Půdorys 1.PP | Suché stavební práce | 1364Dve0000002642 | m3 | Dveřní otvor | NEW | 2.544 | 0.15 | 0.382 | 2.12 | 1.2 | NEMSOK - Object Layer Attributes #1, Směr otevírání dveří: L; Object Layer Attributes #1, Označení: Dveřní otvor; Object Layer Attributes #1, Kód prvku: SN07.02.0001; Object Layer Attributes #1, Podlaží: 1.PP
Dveřní otvor | Půdorys 1.PP | Suché stavební práce | 1364Dve0000006136 | m3 | Dveřní otvor | NEW | 2.544 | 0.15 | 0.382 | 2.12 | 1.2 | NEMSOK - Object Layer Attributes #1, Směr otevírání dveří: P; Object Layer Attributes #1, Označení: Dveřní otvor; Object Layer Attributes #1, Kód prvku: SN07.02.0001; Object Layer Attributes #1, Podlaží: 1.PP
VZT | Půdorys 1.PP | Suché stavební práce | 1364SVý0798585118 | m3 | Stěnový výklenek | NEW | 0.035 | 0.15 | 0.005 | 0.21 | 0.21 | NEMSOK - Object Layer Attributes #1, Označení: VZT; Object Layer Attributes #1, Kód prvku: SN07.02.0001; Object Layer Attributes #1, Podlaží: 1.PP; Object Layer Attributes #1, Rozteč rastru: 625
VZT | Půdorys 1.PP | Suché stavební práce | 1364SVý0798585170 | m3 | Stěnový výklenek | NEW | 0.035 | 0.15 | 0.005 | 0.21 | 0.21 | NEMSOK - Object Layer Attributes #1, Označení: VZT; Object Layer Attributes #1, Kód prvku: SN07.02.0001; Object Layer Attributes #1, Podlaží: 1.PP; Object Layer Attributes #1, Rozteč rastru: 625
Dveřní otvor | Půdorys 1.PP | Suché stavební práce | 1364Dve0000003088 | m3 | Dveřní otvor | NEW | 2.12 | 0.125 | 0.265 | 2.12 | 1 | NEMSOK - Object Layer Attributes #1, Směr otevírání dveří: P; Object Layer Attributes #1, Označení: Dveřní otvor; Object Layer Attributes #1, Kód prvku: SN07.02.0001; Object Layer Attributes #1, Podlaží: 1.PP
UT | Půdorys 1.PP | Suché stavební práce | 1364SVý0798563115 | m3 | Stěnový výklenek | NEW | 0.045 | 0.125 | 0.006 | 0.15 | 0.3 | NEMSOK - Object Layer Attributes #1, Označení: UT; Object Layer Attributes #1, Kód prvku: SN07.02.0001; Object Layer Attributes #1, Podlaží: 1.PP; Object Layer Attributes #1, Rozteč rastru: 625
VZT | Půdorys 1.PP | Suché stavební práce | 1364SVý0798584364 | m3 | Stěnový výklenek | NEW | 0.065 | 0.125 | 0.008 | 0.25 | 0.26 | NEMSOK - Object Layer Attributes #1, Označení: VZT; Object Layer Attributes #1, Kód prvku: SN07.02.0001; Object Layer Attributes #1, Podlaží: 1.PP; Object Layer Attributes #1, Rozteč rastru: 625
UT | Půdorys 1.PP | Suché stavební práce | 1364SVý0798563129 | m3 | Stěnový výklenek | NEW | 0.045 | 0.125 | 0.006 | 0.15 | 0.3 | NEMSOK - Object Layer Attributes #1, Označení: UT; Object Layer Attributes #1, Kód prvku: SN07.02.0001; Object Layer Attributes #1, Podlaží: 1.PP; Object Layer Attributes #1, Rozteč rastru: 625
VZT | Půdorys 1.PP | Suché stavební práce | 1364SVý0798584391 | m3 | Stěnový výklenek | NEW | 0.035 | 0.125 | 0.004 | 0.21 | 0.21 | NEMSOK - Object Layer Attributes #1, Označení: VZT; Object Layer Attributes #1, Kód prvku: SN07.02.0001; Object Layer Attributes #1, Podlaží: 1.PP; Object Layer Attributes #1, Rozteč rastru: 625
Dveřní otvor | Půdorys 1.PP | Suché stavební práce | 1364Dve0000003119 | m3 | Dveřní otvor | NEW | 1.696 | 0.1 | 0.17 | 2.12 | 0.8 | NEMSOK - Object Layer Attributes #1, Směr otevírání dveří: P; Object Layer Attributes #1, Označení: Dveřní otvor; Object Layer Attributes #1, Kód prvku: SN07.02.0001; Object Layer Attributes #1, Podlaží: 1.PP
UT | Půdorys 1.PP | Suché stavební práce | 1364SVý0798563081 | m3 | Stěnový výklenek | NEW | 0.045 | 0.15 | 0.007 | 0.15 | 0.3 | NEMSOK - Object Layer Attributes #1, Označení: UT; Object Layer Attributes #1, Kód prvku: SN07.02.0001; Object Layer Attributes #1, Podlaží: 1.PP; Object Layer Attributes #1, Rozteč rastru: 625
VZT | Půdorys 1.PP | Suché stavební práce | 1364SVý0798584234 | m3 | Stěnový výklenek | NEW | 0.087 | 0.15 | 0.013 | 0.25 | 0.35 | NEMSOK - Object Layer Attributes #1, Označení: VZT; Object Layer Attributes #1, Kód prvku: SN07.02.0001; Object Layer Attributes #1, Podlaží: 1.PP; Object Layer Attributes #1, Rozteč rastru: 625
Dveřní otvor | Půdorys 1.PP | Suché stavební práce | 1364Dve0000007771 | m3 | Dveřní otvor | NEW | 2.544 | 0.125 | 0.318 | 2.12 | 1.2 | NEMSOK - Object Layer Attributes #1, Směr otevírání dveří: L; Object Layer Attributes #1, Označení: Dveřní otvor; Object Layer Attributes #1, Kód prvku: SN07.02.0001; Object Layer Attributes #1, Podlaží: 1.PP
Dveřní otvor | Půdorys 1.PP | Suché stavební práce | 1364Dve0000007821 | m3 | Dveřní otvor | NEW | 2.544 | 0.125 | 0.318 | 2.12 | 1.2 | NEMSOK - Object Layer Attributes #1, Směr otevírání dveří: P; Object Layer Attributes #1, Označení: Dveřní otvor; Object Layer Attributes #1, Kód prvku: SN07.02.0001; Object Layer Attributes #1, Podlaží: 1.PP
Dveřní otvor | Půdorys 1.PP | Suché stavební práce | 1364Dve0000007923 | m3 | Dveřní otvor | NEW | 2.12 | 0.125 | 0.265 | 2.12 | 1 | NEMSOK - Object Layer Attributes #1, Směr otevírání dveří: L; Object Layer Attributes #1, Označení: Dveřní otvor; Object Layer Attributes #1, Kód prvku: SN07.02.0001; Object Layer Attributes #1, Podlaží: 1.PP
Prostup stěnou | Půdorys 1.PP | Suché stavební práce | 1364SNi0798586062 | m3 | Stěnová nika | NEW | 1.83 | 0.1 | 0.183 | 3.05 | 0.6 | NEMSOK - Object Layer Attributes #1, Označení: Prostup stěnou; Object Layer Attributes #1, Kód prvku: SN07.02.0001; Object Layer Attributes #1, Podlaží: 1.PP; Object Layer Attributes #1, Rozteč rastru: 625
Stěnová nika | Půdorys 1.PP | Suché stavební práce | 1364SNi0798587255 | m3 | Stěnová nika | NEW | 1.83 | 0.1 | 0.183 | 3.05 | 0.6 | NEMSOK - Object Layer Attributes #1, Označení: Stěnová nika; Object Layer Attributes #1, Kód prvku: SN07.02.0001; Object Layer Attributes #1, Podlaží: 1.PP; Object Layer Attributes #1, Rozteč rastru: 625
Stěnová nika | Půdorys 1.PP | Suché stavební práce | 1364SNi0798587643 | m3 | Stěnová nika | NEW | 1.83 | 0.1 | 0.183 | 3.05 | 0.6 | NEMSOK - Object Layer Attributes #1, Označení: Stěnová nika; Object Layer Attributes #1, Kód prvku: SN07.02.0001; Object Layer Attributes #1, Podlaží: 1.PP; Object Layer Attributes #1, Rozteč rastru: 625
ZTI | Půdorys 1.PP | Suché stavební práce | 1364SVý0798583271 | m3 | Stěnový výklenek | NEW | 0.019 | 0.125 | 0.002 | 0.11 | 0.175 | NEMSOK - Object Layer Attributes #1, Označení: ZTI; Object Layer Attributes #1, Kód prvku: SN07.02.0001; Object Layer Attributes #1, Podlaží: 1.PP; Object Layer Attributes #1, Rozteč rastru: 625
ZTI | Půdorys 1.PP | Suché stavební práce | 1364SVý0798583290 | m3 | Stěnový výklenek | NEW | 0.056 | 0.125 | 0.007 | 0.15 | 0.37 | NEMSOK - Object Layer Attributes #1, Označení: ZTI; Object Layer Attributes #1, Kód prvku: SN07.02.0001; Object Layer Attributes #1, Podlaží: 1.PP; Object Layer Attributes #1, Rozteč rastru: 625
ZTI | Půdorys 1.PP | Suché stavební práce | 1364SVý0798583308 | m3 | Stěnový výklenek | NEW | 0.019 | 0.125 | 0.002 | 0.11 | 0.175 | NEMSOK - Object Layer Attributes #1, Označení: ZTI; Object Layer Attributes #1, Kód prvku: SN07.02.0001; Object Layer Attributes #1, Podlaží: 1.PP; Object Layer Attributes #1, Rozteč rastru: 625
VZT | Půdorys 1.PP | Suché stavební práce | 1364SVý0798583319 | m3 | Stěnový výklenek | NEW | 0.035 | 0.125 | 0.004 | 0.21 | 0.21 | NEMSOK - Object Layer Attributes #1, Označení: VZT; Object Layer Attributes #1, Kód prvku: SN07.02.0001; Object Layer Attributes #1, Podlaží: 1.PP; Object Layer Attributes #1, Rozteč rastru: 625
VZT | Půdorys 1.PP | Suché stavební práce | 1364SVý0798583373 | m3 | Stěnový výklenek | NEW | 0.035 | 0.125 | 0.004 | 0.21 | 0.21 | NEMSOK - Object Layer Attributes #1, Označení: VZT; Object Layer Attributes #1, Kód prvku: SN07.02.0001; Object Layer Attributes #1, Podlaží: 1.PP; Object Layer Attributes #1, Rozteč rastru: 625
ZTI | Půdorys 1.PP | Suché stavební práce | 1364SVý0798583853 | m3 | Stěnový výklenek | NEW | 0.056 | 0.125 | 0.007 | 0.15 | 0.37 | NEMSOK - Object Layer Attributes #1, Označení: ZTI; Object Layer Attributes #1, Kód prvku: SN07.02.0001; Object Layer Attributes #1, Podlaží: 1.PP; Object Layer Attributes #1, Rozteč rastru: 625
VZT | Půdorys 1.PP | Suché stavební práce | 1364SVý0798583880 | m3 | Stěnový výklenek | NEW | 0.035 | 0.125 | 0.004 | 0.21 | 0.21 | NEMSOK - Object Layer Attributes #1, Označení: VZT; Object Layer Attributes #1, Kód prvku: SN07.02.0001; Object Layer Attributes #1, Podlaží: 1.PP; Object Layer Attributes #1, Rozteč rastru: 625
Dveřní otvor | Půdorys 1.PP | Suché stavební práce | 1364Dve0000007873 | m3 | Dveřní otvor | NEW | 2.544 | 0.125 | 0.318 | 2.12 | 1.2 | NEMSOK - Object Layer Attributes #1, Směr otevírání dveří: P; Object Layer Attributes #1, Označení: Dveřní otvor; Object Layer Attributes #1, Kód prvku: SN07.02.0001; Object Layer Attributes #1, Podlaží: 1.PP
Stěnová nika | Půdorys 1.PP | Suché stavební práce | 1364SNi0798586325 | m3 | Stěnová nika | NEW | 1.525 | 0.025 | 0.038 | 3.05 | 0.5 | NEMSOK - Object Layer Attributes #1, Označení: Stěnová nika; Object Layer Attributes #1, Kód prvku: SN07.02.0001; Object Layer Attributes #1, Podlaží: 1.PP; Object Layer Attributes #1, Rozteč rastru: 625
UT | Půdorys 1.PP | Suché stavební práce | 1364SVý0798583260 | m3 | Stěnový výklenek | NEW | 0.045 | 0.125 | 0.006 | 0.15 | 0.3 | NEMSOK - Object Layer Attributes #1, Označení: UT; Object Layer Attributes #1, Kód prvku: SN07.02.0001; Object Layer Attributes #1, Podlaží: 1.PP; Object Layer Attributes #1, Rozteč rastru: 625
VZT | Půdorys 1.PP | Suché stavební práce | 1364SVý0798584562 | m3 | Stěnový výklenek | NEW | 0.065 | 0.125 | 0.008 | 0.25 | 0.26 | NEMSOK - Object Layer Attributes #1, Označení: VZT; Object Layer Attributes #1, Kód prvku: SN07.02.0001; Object Layer Attributes #1, Podlaží: 1.PP; Object Layer Attributes #1, Rozteč rastru: 625
Okenní otvor | Půdorys 1.PP | Zateplovací systémy | 1364Okn0798563222 | m3 | Okenní otvor | NEW | 0.04 | 0.075 | 0.003 | 0.2 | 0.2 | NEMSOK - Object Layer Attributes #1, Označení: Okenní otvor; Object Layer Attributes #1, Kód prvku: SN07.02.0001; Object Layer Attributes #1, Podlaží: 1.PP; Object Layer Attributes #1, Rozteč rastru: 625
Okenní otvor | Půdorys 1.PP | Zateplovací systémy | 1364Okn0798563139 | m3 | Okenní otvor | NEW | 0.04 | 0.075 | 0.003 | 0.2 | 0.2 | NEMSOK - Object Layer Attributes #1, Označení: Okenní otvor; Object Layer Attributes #1, Kód prvku: SN07.02.0001; Object Layer Attributes #1, Podlaží: 1.PP; Object Layer Attributes #1, Rozteč rastru: 625
Okenní otvor | Půdorys 1.PP | Suché stavební práce | 1364Okn0798563286 | m3 | Stěna | NEW | 0.04 | 0.075 | 0.003 | 0.2 | 0.2 | NEMSOK - Object Layer Attributes #1, Označení: Okenní otvor; Object Layer Attributes #1, Kód prvku: SN07.02.0001; Object Layer Attributes #1, Podlaží: 1.PP; Object Layer Attributes #1, 2D interakce: yes; Object Layer Attributes #1, Staticky nosná konstrukce: no; Object Layer Attributes #1, Statická funkce: Ne; Object Layer Attributes #1, Rozteč rastru: 625; Object Layer Attributes #1, Materiál: SDK ŠACHTOVÁ STĚNA/SDK OPL. S PO
Okenní otvor | Půdorys 1.PP | Suché stavební práce | 1364Okn0798562637 | m3 | Stěna | NEW | 0.16 | 0.075 | 0.012 | 0.4 | 0.4 | NEMSOK - Object Layer Attributes #1, Označení: Okenní otvor; Object Layer Attributes #1, Kód prvku: SN07.02.0001; Object Layer Attributes #1, Podlaží: 1.PP; Object Layer Attributes #1, 2D interakce: yes; Object Layer Attributes #1, Staticky nosná konstrukce: no; Object Layer Attributes #1, Statická funkce: Ne; Object Layer Attributes #1, Rozteč rastru: 625; Object Layer Attributes #1, Materiál: SDK ŠACHTOVÁ STĚNA/SDK OPL. S PO
Okenní otvor | Půdorys 1.PP | Suché stavební práce | 1364Okn0798563268 | m3 | Stěna | NEW | 0.04 | 0.075 | 0.003 | 0.2 | 0.2 | NEMSOK - Object Layer Attributes #1, Označení: Okenní otvor; Object Layer Attributes #1, Kód prvku: SN07.02.0001; Object Layer Attributes #1, Podlaží: 1.PP; Object Layer Attributes #1, 2D interakce: yes; Object Layer Attributes #1, Staticky nosná konstrukce: no; Object Layer Attributes #1, Statická funkce: Ne; Object Layer Attributes #1, Rozteč rastru: 625; Object Layer Attributes #1, Materiál: SDK ŠACHTOVÁ STĚNA/SDK OPL. S PO
Okenní otvor | Půdorys 1.PP | Suché stavební práce | 1364Okn0798562688 | m3 | Stěna | NEW | 0.16 | 0.075 | 0.012 | 0.4 | 0.4 | NEMSOK - Object Layer Attributes #1, Označení: Okenní otvor; Object Layer Attributes #1, Kód prvku: SN07.02.0001; Object Layer Attributes #1, Podlaží: 1.PP; Object Layer Attributes #1, 2D interakce: yes; Object Layer Attributes #1, Staticky nosná konstrukce: no; Object Layer Attributes #1, Statická funkce: Ne; Object Layer Attributes #1, Rozteč rastru: 625; Object Layer Attributes #1, Materiál: SDK ŠACHTOVÁ STĚNA/SDK OPL. S PO
Okenní otvor | Půdorys 1.PP | Suché stavební práce | 1364Okn0798563351 | m3 | Stěna | NEW | 0.04 | 0.075 | 0.003 | 0.2 | 0.2 | NEMSOK - Object Layer Attributes #1, Označení: Okenní otvor; Object Layer Attributes #1, Kód prvku: SN07.02.0001; Object Layer Attributes #1, Podlaží: 1.PP; Object Layer Attributes #1, 2D interakce: yes; Object Layer Attributes #1, Staticky nosná konstrukce: no; Object Layer Attributes #1, Statická funkce: Ne; Object Layer Attributes #1, Rozteč rastru: 625; Object Layer Attributes #1, Materiál: SDK ŠACHTOVÁ STĚNA/SDK OPL. S PO
CHL | Půdorys 1.PP | Suché stavební práce | 1364SVý0798584589 | m3 | Stěna | NEW | 0.018 | 0.075 | 0.001 | 0.15 | 0.15 | NEMSOK - Object Layer Attributes #1, Označení: CHL; Object Layer Attributes #1, Kód prvku: SN07.02.0001; Object Layer Attributes #1, Podlaží: 1.PP; Object Layer Attributes #1, 2D interakce: yes; Object Layer Attributes #1, Staticky nosná konstrukce: no; Object Layer Attributes #1, Statická funkce: Ne; Object Layer Attributes #1, Rozteč rastru: 625; Object Layer Attributes #1, Materiál: SDK ŠACHTOVÁ STĚNA/SDK OPL. S PO
Dveřní otvor | Půdorys 1.PP | Suché stavební práce | 1364Dve0000008289 | m3 | Dveřní otvor | NEW | 2.544 | 0.125 | 0.318 | 2.12 | 1.2 | NEMSOK - Object Layer Attributes #1, Směr otevírání dveří: L; Object Layer Attributes #1, Označení: Dveřní otvor; Object Layer Attributes #1, Kód prvku: SN07.02.0001; Object Layer Attributes #1, Podlaží: 1.PP
Stěnová nika | Půdorys 1.PP | Suché stavební práce | 1364SNi0798586331 | m3 | Stěnová nika | NEW | 1.449 | 0.025 | 0.036 | 3.05 | 0.475 | NEMSOK - Object Layer Attributes #1, Označení: Stěnová nika; Object Layer Attributes #1, Kód prvku: SN07.02.0001; Object Layer Attributes #1, Podlaží: 1.PP; Object Layer Attributes #1, Rozteč rastru: 625
UT | Půdorys 1.PP | Suché stavební práce | 1364SVý0798583246 | m3 | Stěnový výklenek | NEW | 0.045 | 0.125 | 0.006 | 0.15 | 0.3 | NEMSOK - Object Layer Attributes #1, Označení: UT; Object Layer Attributes #1, Kód prvku: SN07.02.0001; Object Layer Attributes #1, Podlaží: 1.PP; Object Layer Attributes #1, Rozteč rastru: 625
VZT | Půdorys 1.PP | Suché stavební práce | 1364SVý0798584597 | m3 | Stěnový výklenek | NEW | 0.1 | 0.125 | 0.013 | 0.25 | 0.4 | NEMSOK - Object Layer Attributes #1, Označení: VZT; Object Layer Attributes #1, Kód prvku: SN07.02.0001; Object Layer Attributes #1, Podlaží: 1.PP; Object Layer Attributes #1, Rozteč rastru: 625
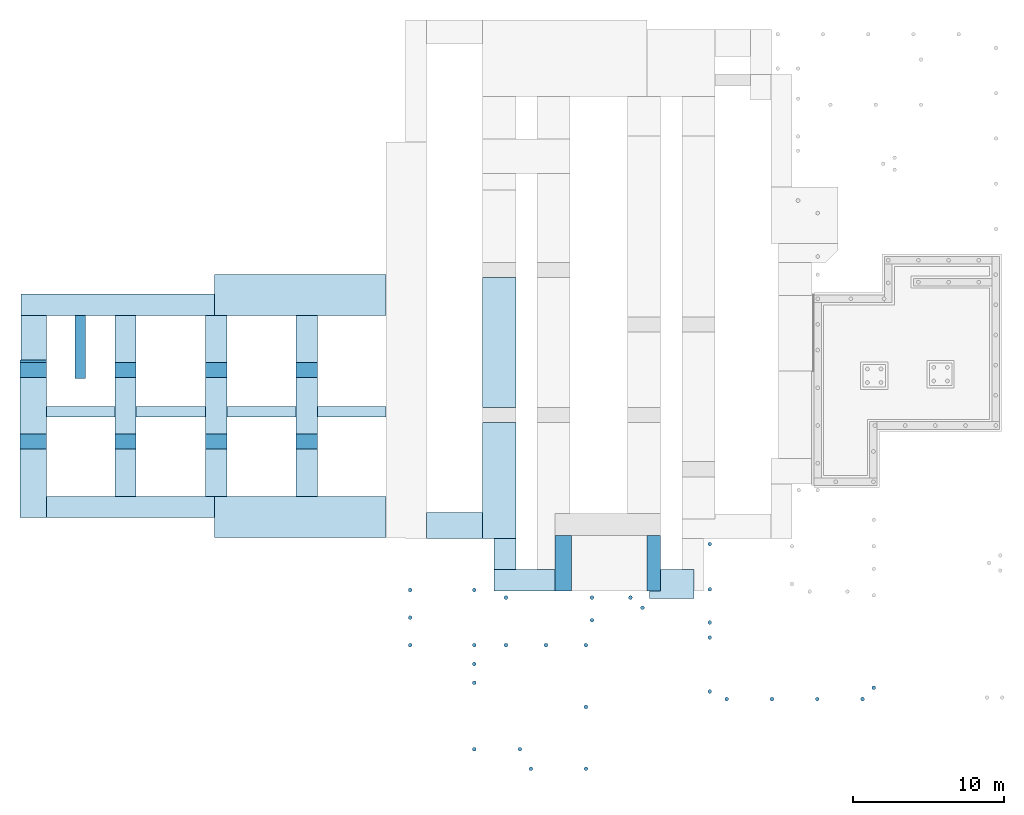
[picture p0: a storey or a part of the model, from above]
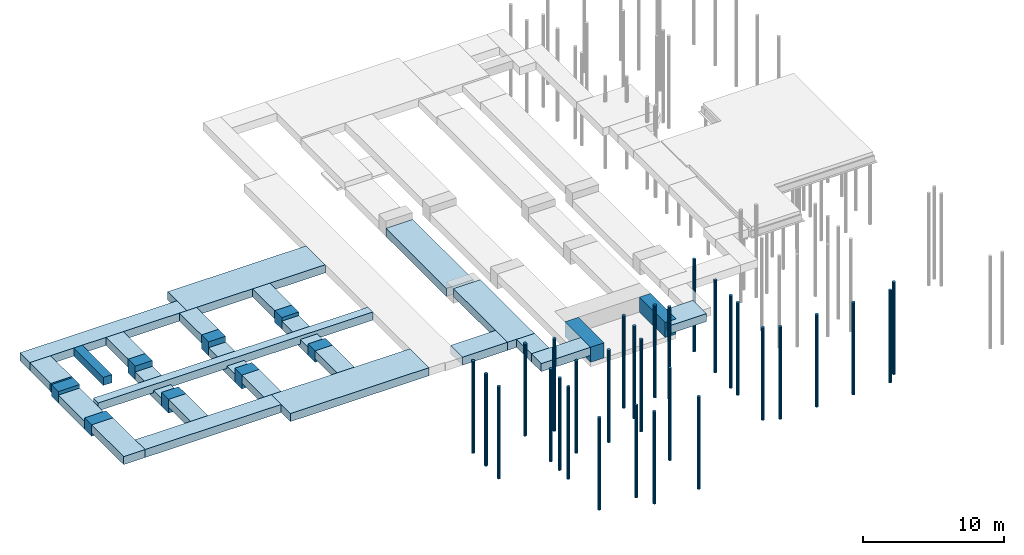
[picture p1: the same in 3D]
Properties of the parts of a building model (IFC4), part 15 of 45

# IfcOpeningElement: Opening (1638)
Name | In | Object Layer Attributes #1, Práce | Object Layer Attributes #1, Allright_Stavebni_dil_ID | Object Layer Attributes #1, Jednotka | Object Layer Attributes #1, Název_objektu | Status | Area (m2) | Depth (m) | Volume (m3) | Height (m) | Width (m)
Dveřní otvor | Půdorys 1.PP | Suché stavební práce | 1364Dve0000009919 | m3 | Dveřní otvor | NEW | 2.12 | 0.125 | 0.265 | 2.12 | 1 | NEMSOK - Object Layer Attributes #1, Směr otevírání dveří: P; Object Layer Attributes #1, Označení: Dveřní otvor; Object Layer Attributes #1, Kód prvku: SN07.02.0001; Object Layer Attributes #1, Podlaží: 1.PP
UT | Půdorys 1.PP | Suché stavební práce | 1364SVý0798563039 | m3 | Stěnový výklenek | NEW | 0.045 | 0.125 | 0.006 | 0.15 | 0.3 | NEMSOK - Object Layer Attributes #1, Označení: UT; Object Layer Attributes #1, Kód prvku: SN07.02.0001; Object Layer Attributes #1, Podlaží: 1.PP; Object Layer Attributes #1, Rozteč rastru: 625
VZT | Půdorys 1.PP | Suché stavební práce | 1364SVý0798563061 | m3 | Stěnový výklenek | NEW | 0.087 | 0.125 | 0.011 | 0.25 | 0.35 | NEMSOK - Object Layer Attributes #1, Označení: VZT; Object Layer Attributes #1, Kód prvku: SN07.02.0001; Object Layer Attributes #1, Podlaží: 1.PP; Object Layer Attributes #1, Rozteč rastru: 625
Dveřní otvor | Půdorys 1.PP | Suché stavební práce | 1364Dve0000010032 | m3 | Dveřní otvor | NEW | 1.696 | 0.1 | 0.17 | 2.12 | 0.8 | NEMSOK - Object Layer Attributes #1, Směr otevírání dveří: P; Object Layer Attributes #1, Označení: Dveřní otvor; Object Layer Attributes #1, Kód prvku: SN07.02.0001; Object Layer Attributes #1, Podlaží: 1.PP
VZT | Půdorys 1.PP | Suché stavební práce | 1364SVý0798585833 | m3 | Stěnový výklenek | NEW | 0.035 | 0.1 | 0.003 | 0.21 | 0.21 | NEMSOK - Object Layer Attributes #1, Označení: VZT; Object Layer Attributes #1, Kód prvku: SN07.02.0001; Object Layer Attributes #1, Podlaží: 1.PP; Object Layer Attributes #1, Rozteč rastru: 625
Stěnová nika | Půdorys 1.PP | Suché stavební práce | 1364SNi0798563466 | m3 | Stěnová nika | NEW | 0.04 | 0.05 | 0.002 | 0.2 | 0.2 | NEMSOK - Object Layer Attributes #1, Označení: Stěnová nika; Object Layer Attributes #1, Kód prvku: SN07.02.0001; Object Layer Attributes #1, Podlaží: 1.PP; Object Layer Attributes #1, Rozteč rastru: 625
Dveřní otvor | Půdorys 1.PP | Suché stavební práce | 1364Dve0000010683 | m3 | Dveřní otvor | NEW | 1.908 | 0.15 | 0.286 | 2.12 | 0.9 | NEMSOK - Object Layer Attributes #1, Směr otevírání dveří: L; Object Layer Attributes #1, Označení: Dveřní otvor; Object Layer Attributes #1, Kód prvku: SN07.02.0001; Object Layer Attributes #1, Podlaží: 1.PP
Prostup stěnou | Půdorys 1.PP | Suché stavební práce | 1364SNi0798586220 | m3 | Stěnová nika | NEW | 1.83 | 0.125 | 0.229 | 3.05 | 0.6 | NEMSOK - Object Layer Attributes #1, Označení: Prostup stěnou; Object Layer Attributes #1, Kód prvku: SN07.02.0001; Object Layer Attributes #1, Podlaží: 1.PP; Object Layer Attributes #1, Rozteč rastru: 625
VZT | Půdorys 1.PP | Suché stavební práce | 1364SVý0798585048 | m3 | Stěnový výklenek | NEW | 0.175 | 0.15 | 0.026 | 0.25 | 0.7 | NEMSOK - Object Layer Attributes #1, Označení: VZT; Object Layer Attributes #1, Kód prvku: SN07.02.0001; Object Layer Attributes #1, Podlaží: 1.PP; Object Layer Attributes #1, Rozteč rastru: 625
UT+ZTI | Půdorys 1.PP | Suché stavební práce | 1364SVý0798585080 | m3 | Stěnový výklenek | NEW | 0.154 | 0.15 | 0.023 | 0.23 | 0.67 | NEMSOK - Object Layer Attributes #1, Označení: UT+ZTI; Object Layer Attributes #1, Kód prvku: SN07.02.0001; Object Layer Attributes #1, Podlaží: 1.PP; Object Layer Attributes #1, Rozteč rastru: 625
VZT | Půdorys 1.PP | Suché stavební práce | 1364SVý0798584858 | m3 | Stěnový výklenek | NEW | 0.17 | 0.1 | 0.017 | 0.25 | 0.68 | NEMSOK - Object Layer Attributes #1, Označení: VZT; Object Layer Attributes #1, Kód prvku: SN07.02.0001; Object Layer Attributes #1, Podlaží: 1.PP; Object Layer Attributes #1, Rozteč rastru: 625
Stěnová nika | Půdorys 1.PP | Suché stavební práce | 1364SNi0798563391 | m3 | Stěnová nika | NEW | 0.04 | 0.05 | 0.002 | 0.2 | 0.2 | NEMSOK - Object Layer Attributes #1, Označení: Stěnová nika; Object Layer Attributes #1, Kód prvku: SN07.02.0001; Object Layer Attributes #1, Podlaží: 1.PP; Object Layer Attributes #1, Rozteč rastru: 625
VZT | Půdorys 1.PP | Suché stavební práce | 1364SVý0798584646 | m3 | Stěnový výklenek | NEW | 0.18 | 0.1 | 0.018 | 0.25 | 0.72 | NEMSOK - Object Layer Attributes #1, Označení: VZT; Object Layer Attributes #1, Kód prvku: SN07.02.0001; Object Layer Attributes #1, Podlaží: 1.PP; Object Layer Attributes #1, Rozteč rastru: 625
Dveřní otvor | Půdorys 1.PP | Suché stavební práce | 1364Dve0000010613 | m3 | Dveřní otvor | NEW | 1.696 | 0.1 | 0.17 | 2.12 | 0.8 | NEMSOK - Object Layer Attributes #1, Směr otevírání dveří: L; Object Layer Attributes #1, Označení: Dveřní otvor; Object Layer Attributes #1, Kód prvku: SN07.02.0001; Object Layer Attributes #1, Podlaží: 1.PP
VZT | Půdorys 1.PP | Suché stavební práce | 1364SVý0798585857 | m3 | Stěnový výklenek | NEW | 0.035 | 0.1 | 0.003 | 0.21 | 0.21 | NEMSOK - Object Layer Attributes #1, Označení: VZT; Object Layer Attributes #1, Kód prvku: SN07.02.0001; Object Layer Attributes #1, Podlaží: 1.PP; Object Layer Attributes #1, Rozteč rastru: 625
Okenní otvor | Půdorys 1.PP | Suché stavební práce | 1364Okn0798562676 | m3 | Stěna | NEW | 0.16 | 0.075 | 0.012 | 0.4 | 0.4 | NEMSOK - Object Layer Attributes #1, Označení: Okenní otvor; Object Layer Attributes #1, Kód prvku: SN07.02.0001; Object Layer Attributes #1, Podlaží: 1.PP; Object Layer Attributes #1, 2D interakce: yes; Object Layer Attributes #1, Staticky nosná konstrukce: no; Object Layer Attributes #1, Statická funkce: Ne; Object Layer Attributes #1, Rozteč rastru: 625; Object Layer Attributes #1, Materiál: SDK ŠACHTOVÁ STĚNA/SDK OPL. S PO
ZTI | Půdorys 1.PP | Suché stavební práce | 1364SVý0798584768 | m3 | Stěna | NEW | 0.056 | 0.075 | 0.004 | 0.15 | 0.37 | NEMSOK - Object Layer Attributes #1, Označení: ZTI; Object Layer Attributes #1, Kód prvku: SN07.02.0001; Object Layer Attributes #1, Podlaží: 1.PP; Object Layer Attributes #1, 2D interakce: yes; Object Layer Attributes #1, Staticky nosná konstrukce: no; Object Layer Attributes #1, Statická funkce: Ne; Object Layer Attributes #1, Rozteč rastru: 625; Object Layer Attributes #1, Materiál: SDK ŠACHTOVÁ STĚNA/SDK OPL. S PO
VZT | Půdorys 1.PP | Suché stavební práce | 1364SVý0798584840 | m3 | Stěnový výklenek | NEW | 0.049 | 0.15 | 0.007 | 0.25 | 0.25 | NEMSOK - Object Layer Attributes #1, Označení: VZT; Object Layer Attributes #1, Kód prvku: SN07.02.0001; Object Layer Attributes #1, Podlaží: 1.PP; Object Layer Attributes #1, Rozteč rastru: 625
Dveřní otvor | Půdorys 1.PP | Suché stavební práce | 1364Dve0000010762 | m3 | Dveřní otvor | NEW | 1.696 | 0.1 | 0.17 | 2.12 | 0.8 | NEMSOK - Object Layer Attributes #1, Směr otevírání dveří: P; Object Layer Attributes #1, Označení: Dveřní otvor; Object Layer Attributes #1, Kód prvku: SN07.02.0001; Object Layer Attributes #1, Podlaží: 1.PP
VZT | Půdorys 1.PP | Suché stavební práce | 1364SVý0798585025 | m3 | Stěnový výklenek | NEW | 0.035 | 0.1 | 0.003 | 0.21 | 0.21 | NEMSOK - Object Layer Attributes #1, Označení: VZT; Object Layer Attributes #1, Kód prvku: SN07.02.0001; Object Layer Attributes #1, Podlaží: 1.PP; Object Layer Attributes #1, Rozteč rastru: 625
Dveřní otvor | Půdorys 1.PP | Suché stavební práce | 1364Dve0000010755 | m3 | Dveřní otvor | NEW | 1.696 | 0.1 | 0.17 | 2.12 | 0.8 | NEMSOK - Object Layer Attributes #1, Směr otevírání dveří: L; Object Layer Attributes #1, Označení: Dveřní otvor; Object Layer Attributes #1, Kód prvku: SN07.02.0001; Object Layer Attributes #1, Podlaží: 1.PP
VZT | Půdorys 1.PP | Suché stavební práce | 1364SVý0798584974 | m3 | Stěnový výklenek | NEW | 0.035 | 0.1 | 0.003 | 0.21 | 0.21 | NEMSOK - Object Layer Attributes #1, Označení: VZT; Object Layer Attributes #1, Kód prvku: SN07.02.0001; Object Layer Attributes #1, Podlaží: 1.PP; Object Layer Attributes #1, Rozteč rastru: 625
VZT | Půdorys 1.PP | Suché stavební práce | 1364SVý0798585000 | m3 | Stěnový výklenek | NEW | 0.049 | 0.1 | 0.005 | 0.25 | 0.25 | NEMSOK - Object Layer Attributes #1, Označení: VZT; Object Layer Attributes #1, Kód prvku: SN07.02.0001; Object Layer Attributes #1, Podlaží: 1.PP; Object Layer Attributes #1, Rozteč rastru: 625
Stěnová nika | Půdorys 1.PP | Suché stavební práce | 1364SNi0798563422 | m3 | Stěnová nika | NEW | 0.04 | 0.05 | 0.002 | 0.2 | 0.2 | NEMSOK - Object Layer Attributes #1, Označení: Stěnová nika; Object Layer Attributes #1, Kód prvku: SN07.02.0001; Object Layer Attributes #1, Podlaží: 1.PP; Object Layer Attributes #1, Rozteč rastru: 625
VZT | Půdorys 1.PP | Suché stavební práce | 1364SVý0798584816 | m3 | Stěnový výklenek | NEW | 0.049 | 0.25 | 0.012 | 0.25 | 0.25 | NEMSOK - Object Layer Attributes #1, Označení: VZT; Object Layer Attributes #1, Kód prvku: SN07.02.0001; Object Layer Attributes #1, Podlaží: 1.PP; Object Layer Attributes #1, Rozteč rastru: 625
VZT | Půdorys 1.PP | Suché stavební práce | 1364SVý0798584798 | m3 | Stěnový výklenek | NEW | 0.088 | 0.1 | 0.009 | 0.21 | 0.42 | NEMSOK - Object Layer Attributes #1, Označení: VZT; Object Layer Attributes #1, Kód prvku: SN07.02.0001; Object Layer Attributes #1, Podlaží: 1.PP; Object Layer Attributes #1, Rozteč rastru: 625
Dveřní otvor | Půdorys 1.PP | Suché stavební práce | 1364Dve0000010737 | m3 | Dveřní otvor | NEW | 1.908 | 0.125 | 0.238 | 2.12 | 0.9 | NEMSOK - Object Layer Attributes #1, Směr otevírání dveří: L; Object Layer Attributes #1, Označení: Dveřní otvor; Object Layer Attributes #1, Kód prvku: SN07.02.0001; Object Layer Attributes #1, Podlaží: 1.PP
Dveřní otvor | Půdorys 1.PP | Suché stavební práce | 1364Dve0000011120 | m3 | Dveřní otvor | NEW | 1.908 | 0.125 | 0.238 | 2.12 | 0.9 | NEMSOK - Object Layer Attributes #1, Směr otevírání dveří: L; Object Layer Attributes #1, Označení: Dveřní otvor; Object Layer Attributes #1, Kód prvku: SN07.02.0001; Object Layer Attributes #1, Podlaží: 1.PP
Dveřní otvor | Půdorys 1.PP | Suché stavební práce | 1364Dve0000011123 | m3 | Dveřní otvor | NEW | 1.908 | 0.125 | 0.238 | 2.12 | 0.9 | NEMSOK - Object Layer Attributes #1, Směr otevírání dveří: L; Object Layer Attributes #1, Označení: Dveřní otvor; Object Layer Attributes #1, Kód prvku: SN07.02.0001; Object Layer Attributes #1, Podlaží: 1.PP
Prostup stěnou | Půdorys 1.PP | Suché stavební práce | 1364SNi0798586256 | m3 | Stěnová nika | NEW | 1.83 | 0.1 | 0.183 | 3.05 | 0.6 | NEMSOK - Object Layer Attributes #1, Označení: Prostup stěnou; Object Layer Attributes #1, Kód prvku: SN07.02.0001; Object Layer Attributes #1, Podlaží: 1.PP; Object Layer Attributes #1, Rozteč rastru: 625
VZT | Půdorys 1.PP | Suché stavební práce | 1364SVý0798584886 | m3 | Stěnový výklenek | NEW | 0.17 | 0.125 | 0.021 | 0.25 | 0.68 | NEMSOK - Object Layer Attributes #1, Označení: VZT; Object Layer Attributes #1, Kód prvku: SN07.02.0001; Object Layer Attributes #1, Podlaží: 1.PP; Object Layer Attributes #1, Rozteč rastru: 625
VZT | Půdorys 1.PP | Suché stavební práce | 1364SVý0798584914 | m3 | Stěnový výklenek | NEW | 0.065 | 0.125 | 0.008 | 0.25 | 0.26 | NEMSOK - Object Layer Attributes #1, Označení: VZT; Object Layer Attributes #1, Kód prvku: SN07.02.0001; Object Layer Attributes #1, Podlaží: 1.PP; Object Layer Attributes #1, Rozteč rastru: 625
ZTI | Půdorys 1.PP | Suché stavební práce | 1364SVý0798584954 | m3 | Stěnový výklenek | NEW | 0.019 | 0.125 | 0.002 | 0.11 | 0.175 | NEMSOK - Object Layer Attributes #1, Označení: ZTI; Object Layer Attributes #1, Kód prvku: SN07.02.0001; Object Layer Attributes #1, Podlaží: 1.PP; Object Layer Attributes #1, Rozteč rastru: 625
Dveřní otvor | Půdorys 1.PP | Suché stavební práce | 1364Dve0798585512 | m3 | Stěna | NEW | 1.2 | 0.075 | 0.09 | 2 | 0.6 | NEMSOK - Object Layer Attributes #1, Směr otevírání dveří: -; Object Layer Attributes #1, Označení: Dveřní otvor; Object Layer Attributes #1, Kód prvku: SN07.02.0001; Object Layer Attributes #1, Podlaží: 1.PP; Object Layer Attributes #1, 2D interakce: yes; Object Layer Attributes #1, Staticky nosná konstrukce: no; Object Layer Attributes #1, Statická funkce: Ne; Object Layer Attributes #1, Materiál: SDK ŠACHTOVÁ STĚNA/SDK OPL. S PO
Okenní otvor | Půdorys 1.PP | Suché stavební práce | 1364Okn0798563502 | m3 | Stěna | NEW | 0.09 | 0.075 | 0.007 | 0.3 | 0.3 | NEMSOK - Object Layer Attributes #1, Označení: Okenní otvor; Object Layer Attributes #1, Kód prvku: SN07.02.0001; Object Layer Attributes #1, Podlaží: 1.PP; Object Layer Attributes #1, 2D interakce: yes; Object Layer Attributes #1, Staticky nosná konstrukce: no; Object Layer Attributes #1, Statická funkce: Ne; Object Layer Attributes #1, Rozteč rastru: 625; Object Layer Attributes #1, Materiál: SDK ŠACHTOVÁ STĚNA/SDK OPL. S PO
ZTI | Půdorys 1.PP | Suché stavební práce | 1364SVý0798585349 | m3 | Stěna | NEW | 0.055 | 0.075 | 0.004 | 0.15 | 0.37 | NEMSOK - Object Layer Attributes #1, Označení: ZTI; Object Layer Attributes #1, Kód prvku: SN07.02.0001; Object Layer Attributes #1, Podlaží: 1.PP; Object Layer Attributes #1, 2D interakce: yes; Object Layer Attributes #1, Staticky nosná konstrukce: no; Object Layer Attributes #1, Statická funkce: Ne; Object Layer Attributes #1, Rozteč rastru: 625; Object Layer Attributes #1, Materiál: SDK ŠACHTOVÁ STĚNA/SDK OPL. S PO
Okenní otvor | Půdorys 1.PP | Suché stavební práce | 1364Okn0798563551 | m3 | Stěna | NEW | 0.09 | 0.075 | 0.007 | 0.3 | 0.3 | NEMSOK - Object Layer Attributes #1, Označení: Okenní otvor; Object Layer Attributes #1, Kód prvku: SN07.02.0001; Object Layer Attributes #1, Podlaží: 1.PP; Object Layer Attributes #1, 2D interakce: yes; Object Layer Attributes #1, Staticky nosná konstrukce: no; Object Layer Attributes #1, Statická funkce: Ne; Object Layer Attributes #1, Rozteč rastru: 625; Object Layer Attributes #1, Materiál: SDK ŠACHTOVÁ STĚNA/SDK OPL. S PO
ZTI | Půdorys 1.PP | Suché stavební práce | 1364SVý0798585310 | m3 | Stěna | NEW | 0.055 | 0.075 | 0.004 | 0.15 | 0.37 | NEMSOK - Object Layer Attributes #1, Označení: ZTI; Object Layer Attributes #1, Kód prvku: SN07.02.0001; Object Layer Attributes #1, Podlaží: 1.PP; Object Layer Attributes #1, 2D interakce: yes; Object Layer Attributes #1, Staticky nosná konstrukce: no; Object Layer Attributes #1, Statická funkce: Ne; Object Layer Attributes #1, Rozteč rastru: 625; Object Layer Attributes #1, Materiál: SDK ŠACHTOVÁ STĚNA/SDK OPL. S PO
Okenní otvor | Půdorys 1.PP | Suché stavební práce | 1364Okn0798563487 | m3 | Stěna | NEW | 0.04 | 0.075 | 0.003 | 0.2 | 0.2 | NEMSOK - Object Layer Attributes #1, Označení: Okenní otvor; Object Layer Attributes #1, Kód prvku: SN07.02.0001; Object Layer Attributes #1, Podlaží: 1.PP; Object Layer Attributes #1, 2D interakce: yes; Object Layer Attributes #1, Staticky nosná konstrukce: no; Object Layer Attributes #1, Statická funkce: Ne; Object Layer Attributes #1, Rozteč rastru: 625; Object Layer Attributes #1, Materiál: SDK ŠACHTOVÁ STĚNA/SDK OPL. S PO
Okenní otvor | Půdorys 1.PP | Zateplovací systémy | 1364Okn0798563570 | m3 | Okenní otvor | NEW | 0.09 | 0.075 | 0.007 | 0.3 | 0.3 | NEMSOK - Object Layer Attributes #1, Označení: Okenní otvor; Object Layer Attributes #1, Kód prvku: SN07.02.0001; Object Layer Attributes #1, Podlaží: 1.PP; Object Layer Attributes #1, Rozteč rastru: 625
ZTI | Půdorys 1.PP | Suché stavební práce | 1364SVý0798584431 | m3 | Stěnový výklenek | NEW | 0.056 | 0.075 | 0.004 | 0.15 | 0.37 | NEMSOK - Object Layer Attributes #1, Označení: ZTI; Object Layer Attributes #1, Kód prvku: SN07.02.0001; Object Layer Attributes #1, Podlaží: 1.PP; Object Layer Attributes #1, Rozteč rastru: 625
VZT | Půdorys 1.PP | Suché stavební práce | 1364SVý0798562903 | m3 | Stěnový výklenek | NEW | 0.04 | 0.125 | 0.005 | 0.225 | 0.225 | NEMSOK - Object Layer Attributes #1, Označení: VZT; Object Layer Attributes #1, Kód prvku: SN07.02.0001; Object Layer Attributes #1, Podlaží: 1.PP; Object Layer Attributes #1, Rozteč rastru: 625
UT | Půdorys 1.PP | Suché stavební práce | 1364SVý0798562935 | m3 | Stěnový výklenek | NEW | 0.045 | 0.125 | 0.006 | 0.15 | 0.3 | NEMSOK - Object Layer Attributes #1, Označení: UT; Object Layer Attributes #1, Kód prvku: SN07.02.0001; Object Layer Attributes #1, Podlaží: 1.PP; Object Layer Attributes #1, Rozteč rastru: 625
UT | Půdorys 1.PP | Suché stavební práce | 1364SVý0798592052 | m3 | Stěnový výklenek | NEW | 0.03 | 0.125 | 0.004 | 0.12 | 0.25 | NEMSOK - Object Layer Attributes #1, Označení: UT; Object Layer Attributes #1, Kód prvku: SN07.02.0001; Object Layer Attributes #1, Podlaží: 1.PP; Object Layer Attributes #1, Rozteč rastru: 625
Dveřní otvor | Půdorys 1.PP | Suché stavební práce | 1364Dve0798495723 | m3 | Dveřní otvor | NEW | 2.32 | 0.15 | 0.348 | 2.32 | 1 | NEMSOK - Object Layer Attributes #1, Směr otevírání dveří: P; Object Layer Attributes #1, Označení: Dveřní otvor; Object Layer Attributes #1, Kód prvku: SN07.02.0001; Object Layer Attributes #1, Podlaží: 1.PP
VZT | Půdorys 1.PP | Suché stavební práce | 1364SVý0798562377 | m3 | Stěnový výklenek | NEW | 0.04 | 0.15 | 0.006 | 0.225 | 0.225 | NEMSOK - Object Layer Attributes #1, Označení: VZT; Object Layer Attributes #1, Kód prvku: SN07.02.0001; Object Layer Attributes #1, Podlaží: 1.PP; Object Layer Attributes #1, Rozteč rastru: 625
ZTI | Půdorys 1.PP | Suché stavební práce | 1364SVý0798583166 | m3 | Stěnový výklenek | NEW | 0.033 | 0.15 | 0.005 | 0.11 | 0.3 | NEMSOK - Object Layer Attributes #1, Označení: ZTI; Object Layer Attributes #1, Kód prvku: SN07.02.0001; Object Layer Attributes #1, Podlaží: 1.PP; Object Layer Attributes #1, Rozteč rastru: 625
VZT | Půdorys 1.PP | Suché stavební práce | 1364SVý0798562403 | m3 | Stěnový výklenek | NEW | 0.04 | 0.15 | 0.006 | 0.225 | 0.225 | NEMSOK - Object Layer Attributes #1, Označení: VZT; Object Layer Attributes #1, Kód prvku: SN07.02.0001; Object Layer Attributes #1, Podlaží: 1.PP; Object Layer Attributes #1, Rozteč rastru: 625
VZT | Půdorys 1.PP | Suché stavební práce | 1364SVý0798562597 | m3 | Stěnový výklenek | NEW | 0.04 | 0.15 | 0.006 | 0.225 | 0.225 | NEMSOK - Object Layer Attributes #1, Označení: VZT; Object Layer Attributes #1, Kód prvku: SN07.02.0001; Object Layer Attributes #1, Podlaží: 1.PP; Object Layer Attributes #1, Rozteč rastru: 625
Dveřní otvor | Půdorys 1.PP | Suché stavební práce | 1364Dve0798495657 | m3 | Dveřní otvor | NEW | 2.32 | 0.15 | 0.348 | 2.32 | 1 | NEMSOK - Object Layer Attributes #1, Směr otevírání dveří: L; Object Layer Attributes #1, Označení: Dveřní otvor; Object Layer Attributes #1, Kód prvku: SN07.02.0001; Object Layer Attributes #1, Podlaží: 1.PP
Dveřní otvor | Půdorys 1.PP | Suché stavební práce | 1364Dve0798498435 | m3 | Dveřní otvor | NEW | 4.408 | 0.15 | 0.661 | 2.32 | 1.9 | NEMSOK - Object Layer Attributes #1, Směr otevírání dveří: -; Object Layer Attributes #1, Označení: Dveřní otvor; Object Layer Attributes #1, Kód prvku: SN07.02.0001; Object Layer Attributes #1, Podlaží: 1.PP
VZT | Půdorys 1.PP | Suché stavební práce | 1364SVý0798562555 | m3 | Stěnový výklenek | NEW | 0.431 | 0.15 | 0.065 | 0.325 | 1.325 | NEMSOK - Object Layer Attributes #1, Označení: VZT; Object Layer Attributes #1, Kód prvku: SN07.02.0001; Object Layer Attributes #1, Podlaží: 1.PP; Object Layer Attributes #1, Rozteč rastru: 625
VZT | Půdorys 1.PP | Suché stavební práce | 1364SVý0798583139 | m3 | Stěnový výklenek | NEW | 0.04 | 0.15 | 0.006 | 0.225 | 0.225 | NEMSOK - Object Layer Attributes #1, Označení: VZT; Object Layer Attributes #1, Kód prvku: SN07.02.0001; Object Layer Attributes #1, Podlaží: 1.PP; Object Layer Attributes #1, Rozteč rastru: 625
VZT | Půdorys 1.PP | Suché stavební práce | 1364SVý0798583782 | m3 | Stěnový výklenek | NEW | 0.04 | 0.15 | 0.006 | 0.225 | 0.225 | NEMSOK - Object Layer Attributes #1, Označení: VZT; Object Layer Attributes #1, Kód prvku: SN07.02.0001; Object Layer Attributes #1, Podlaží: 1.PP; Object Layer Attributes #1, Rozteč rastru: 625
VZT | Půdorys 1.PP | Suché stavební práce | 1364SVý0798562290 | m3 | Stěnový výklenek | NEW | 0.04 | 0.15 | 0.006 | 0.225 | 0.225 | NEMSOK - Object Layer Attributes #1, Označení: VZT; Object Layer Attributes #1, Kód prvku: SN07.02.0001; Object Layer Attributes #1, Podlaží: 1.PP; Object Layer Attributes #1, Rozteč rastru: 625
Dveřní otvor | Půdorys 1.PP | Suché stavební práce | 1364Dve0798498707 | m3 | Dveřní otvor | NEW | 2.32 | 0.15 | 0.348 | 2.32 | 1 | NEMSOK - Object Layer Attributes #1, Směr otevírání dveří: P; Object Layer Attributes #1, Označení: Dveřní otvor; Object Layer Attributes #1, Kód prvku: SN07.02.0001; Object Layer Attributes #1, Podlaží: 1.PP
VZT | Půdorys 1.PP | Suché stavební práce | 1364SVý0798562329 | m3 | Stěnový výklenek | NEW | 0.04 | 0.15 | 0.006 | 0.225 | 0.225 | NEMSOK - Object Layer Attributes #1, Označení: VZT; Object Layer Attributes #1, Kód prvku: SN07.02.0001; Object Layer Attributes #1, Podlaží: 1.PP; Object Layer Attributes #1, Rozteč rastru: 625
VZT | Půdorys 1.PP | Suché stavební práce | 1364SVý0798562351 | m3 | Stěnový výklenek | NEW | 0.358 | 0.15 | 0.054 | 0.325 | 1.1 | NEMSOK - Object Layer Attributes #1, Označení: VZT; Object Layer Attributes #1, Kód prvku: SN07.02.0001; Object Layer Attributes #1, Podlaží: 1.PP; Object Layer Attributes #1, Rozteč rastru: 625
VZT | Půdorys 1.PP | Suché stavební práce | 1364SVý0798584421 | m3 | Stěnový výklenek | NEW | 0.035 | 0.125 | 0.004 | 0.21 | 0.21 | NEMSOK - Object Layer Attributes #1, Označení: VZT; Object Layer Attributes #1, Kód prvku: SN07.02.0001; Object Layer Attributes #1, Podlaží: 1.PP; Object Layer Attributes #1, Rozteč rastru: 625
VZT | Půdorys 1.PP | Suché stavební práce | 1364SVý0798585202 | m3 | Stěnový výklenek | NEW | 0.035 | 0.25 | 0.009 | 0.21 | 0.21 | NEMSOK - Object Layer Attributes #1, Označení: VZT; Object Layer Attributes #1, Kód prvku: SN07.02.0001; Object Layer Attributes #1, Podlaží: 1.PP; Object Layer Attributes #1, Rozteč rastru: 625
ZTI | Půdorys 1.PP | Suché stavební práce | 1364SVý0798585221 | m3 | Stěnový výklenek | NEW | 0.056 | 0.25 | 0.014 | 0.15 | 0.37 | NEMSOK - Object Layer Attributes #1, Označení: ZTI; Object Layer Attributes #1, Kód prvku: SN07.02.0001; Object Layer Attributes #1, Podlaží: 1.PP; Object Layer Attributes #1, Rozteč rastru: 625
Prostup deskou | Půdorys 1.PP | Betonářské práce | 1366DOt0000000021 | m3 | Otvor v desce | NEW | 1.35 | 1.5 | 0.27 | 0.2 | 0.9 | NEMSOK - Object Layer Attributes #1, Označení: Prostup deskou
Prostup deskou | Půdorys 1.PP | Betonářské práce | 1366DOt0000000064 | m3 | Otvor v desce | NEW | 0.63 | 0.9 | 0.158 | 0.25 | 0.7 | NEMSOK - Object Layer Attributes #1, Označení: Prostup deskou
Prostup deskou | Půdorys 1.PP | Betonářské práce | 1366DOt0000000082 | m3 | Otvor v desce | NEW | 0.031 | 0.157 | 0.008 | 0.25 | 0.2 | NEMSOK - Object Layer Attributes #1, Označení: Prostup deskou
Prostup deskou | Půdorys 1.PP | Betonářské práce | 1366DOt0000000095 | m3 | Otvor v desce | NEW | 0.026 | 0.12 | 0.007 | 0.25 | 0.22
Dveřní otvor | Půdorys 1.NP | Betonářské práce | 1452Dve0798445809 | m3 | Dveřní otvor | NEW | 3.78 | 0.5 | 1.89 | 2.1 | 1.8 | NEMSOK - Object Layer Attributes #1, Směr otevírání dveří: -
Okenní otvor | Půdorys 1.NP | Zateplovací systémy | 1452Okn0000003883 | m3 | Okenní otvor | NEW | 3.15 | 0.32 | 1.008 | 2.1 | 1.5
Okenní otvor | Půdorys 1.NP | Zateplovací systémy | 1452Okn0000003922 | m3 | Okenní otvor | NEW | 3.15 | 0.32 | 1.008 | 2.1 | 1.5
Okenní otvor | Půdorys 1.NP | Zateplovací systémy | 1452Okn0000003928 | m3 | Okenní otvor | NEW | 3.15 | 0.32 | 1.008 | 2.1 | 1.5
Okenní otvor | Půdorys 1.NP | Zateplovací systémy | 1452Okn0000003934 | m3 | Okenní otvor | NEW | 3.15 | 0.32 | 1.008 | 2.1 | 1.5
Okenní otvor | Půdorys 1.NP | Zateplovací systémy | 1452Okn0000003940 | m3 | Okenní otvor | NEW | 3.15 | 0.32 | 1.008 | 2.1 | 1.5
Okenní otvor | Půdorys 1.NP | Zateplovací systémy | 1452Okn0000003946 | m3 | Okenní otvor | NEW | 3.15 | 0.32 | 1.008 | 2.1 | 1.5
Okenní otvor | Půdorys 1.NP | Zateplovací systémy | 1452Okn0000003952 | m3 | Okenní otvor | NEW | 3.15 | 0.32 | 1.008 | 2.1 | 1.5
Okenní otvor | Půdorys 1.NP | Zateplovací systémy | 1452Okn0000003890 | m3 | Okenní otvor | NEW | 3.15 | 0.32 | 1.008 | 2.1 | 1.5
Dveřní otvor | Půdorys 1.NP | Betonářské práce | 1452Dve0000004860 | m3 | Dveřní otvor | NEW | 7.68 | 0.3 | 2.304 | 3.2 | 2.4 | NEMSOK - Object Layer Attributes #1, Směr otevírání dveří: -
Okenní otvor | Půdorys 1.NP | Zateplovací systémy | 1452Okn0798422975 | m3 | Okenní otvor | NEW | 3 | 0.3 | 0.9 | 2 | 1.5
Okenní otvor | Půdorys 1.NP | Zateplovací systémy | 1452Okn0000004796 | m3 | Okenní otvor | NEW | 3.15 | 0.3 | 0.945 | 2.1 | 1.5
Okenní otvor | Půdorys 1.NP | Zateplovací systémy | 1452Okn0000004137 | m3 | Okenní otvor | NEW | 3.15 | 0.32 | 1.008 | 2.1 | 1.5
Okenní otvor | Půdorys 1.NP | Zateplovací systémy | 1452Okn0000004140 | m3 | Okenní otvor | NEW | 3.15 | 0.32 | 1.008 | 2.1 | 1.5
Okenní otvor | Půdorys 1.NP | Zateplovací systémy | 1452Okn0000004143 | m3 | Okenní otvor | NEW | 3.15 | 0.32 | 1.008 | 2.1 | 1.5
Okenní otvor | Půdorys 1.NP | Zateplovací systémy | 1452Okn0000004146 | m3 | Okenní otvor | NEW | 3.15 | 0.32 | 1.008 | 2.1 | 1.5
Okenní otvor | Půdorys 1.NP | Zateplovací systémy | 1452Okn0000004152 | m3 | Okenní otvor | NEW | 3.15 | 0.32 | 1.008 | 2.1 | 1.5
Okenní otvor | Půdorys 1.NP | Zateplovací systémy | 1452Okn0000004158 | m3 | Okenní otvor | NEW | 3.15 | 0.32 | 1.008 | 2.1 | 1.5
Okenní otvor | Půdorys 1.NP | Zateplovací systémy | 1452Okn0000004155 | m3 | Okenní otvor | NEW | 3.15 | 0.32 | 1.008 | 2.1 | 1.5
Okenní otvor | Půdorys 1.NP | Zateplovací systémy | 1452Okn0000004149 | m3 | Okenní otvor | NEW | 3.15 | 0.32 | 1.008 | 2.1 | 1.5
UT | Půdorys 1.NP | Suché stavební práce | 1452SVý1096220763 | m3 | Stěnový výklenek |  | 0.03 | 0.32 | 0.01 | 0.25 | 0.12 | NEMSOK - Object Layer Attributes #1, Označení: UT; Object Layer Attributes #1, Vnější průměr: 1010431516015xxxxxxx0
Prostup stěnou | Půdorys 1.NP | Betonářské práce | 1452SVý1096220548 | m3 | Stěnový výklenek | NEW | 0.008 | 0.3 | 0.002 | 0.1 | 0.1
Dveřní otvor | Půdorys 1.NP | Betonářské práce | 1452Dve1096117127 | m3 | Dveřní otvor | NEW | 2.424 | 0.25 | 0.606 | 2.02 | 1.2 | NEMSOK - Object Layer Attributes #1, Směr otevírání dveří: L
Dveřní otvor | Půdorys 1.NP | Betonářské práce | 1452Dve0798434325 | m3 | Dveřní otvor | NEW | 3.503 | 0.25 | 0.876 | 2.26 | 1.55 | NEMSOK - Object Layer Attributes #1, Směr otevírání dveří: -
Dveřní otvor | Půdorys 1.NP | Betonářské práce | 1452Dve0798434323 | m3 | Dveřní otvor | NEW | 3.503 | 0.25 | 0.876 | 2.26 | 1.55 | NEMSOK - Object Layer Attributes #1, Směr otevírání dveří: -
CHL | Půdorys 1.NP | Suché stavební práce | 1452SVý1096221534 | m3 | Stěna | NEW | 0.031 | 0.953 | 0.03 | 0.2 | 0.2 | NEMSOK - Object Layer Attributes #1, Označení: CHL; Object Layer Attributes #1, Podlaží: 1.NP; Object Layer Attributes #1, 2D interakce: yes; Object Layer Attributes #1, Staticky nosná konstrukce: no
Okenní otvor | Půdorys 1.NP | Zateplovací systémy | 1452Okn0798418617 | m3 | Okenní otvor | NEW | 2.925 | 0.32 | 0.936 | 1.95 | 1.5
Okenní otvor | Půdorys 1.NP | Zateplovací systémy | 1452Okn0798418681 | m3 | Okenní otvor | NEW | 2.925 | 0.32 | 0.936 | 1.95 | 1.5
Okenní otvor | Půdorys 1.NP | Zateplovací systémy | 1452Okn0798418711 | m3 | Okenní otvor | NEW | 2.925 | 0.32 | 0.936 | 1.95 | 1.5
Okenní otvor | Půdorys 1.NP | Zateplovací systémy | 1452Okn0798418794 | m3 | Okenní otvor | NEW | 2.16 | 0.32 | 0.691 | 1.8 | 1.2
Okenní otvor | Půdorys 1.NP | Zateplovací systémy | 1452Okn0798418855 | m3 | Okenní otvor | NEW | 2.16 | 0.32 | 0.691 | 1.8 | 1.2
Okenní otvor | Půdorys 1.NP | Zateplovací systémy | 1452Okn0798418919 | m3 | Okenní otvor | NEW | 2.16 | 0.32 | 0.691 | 1.8 | 1.2
Dveřní otvor | Půdorys 1.NP | Betonářské práce | 1452Dve0798426956 | m3 | Dveřní otvor | NEW | 3.72 | 0.32 | 1.19 | 3.1 | 1.2 | NEMSOK - Object Layer Attributes #1, Směr otevírání dveří: L
Okenní otvor | Půdorys 1.NP | Zateplovací systémy | 1452Okn0798429433 | m3 | Okenní otvor | NEW | 2.047 | 0.32 | 0.655 | 1.95 | 1.05
UT | Půdorys 1.NP | Betonářské práce | 1452SVý1096221742 | m3 | Stěnový výklenek | NEW | 0.034 | 0.3 | 0.01 | 0.12 | 0.28 | NEMSOK - Object Layer Attributes #1, Označení: UT
ZTI | Půdorys 1.NP | Betonářské práce | 1452SVý1096221058 | m3 | Stěnový výklenek | NEW | 0.031 | 0.3 | 0.009 | 0.2 | 0.2 | NEMSOK - Object Layer Attributes #1, Označení: ZTI
VZT | Půdorys 1.NP | Suché stavební práce | 1452SVý1096221110 | m3 | Stěnový výklenek |  | 0.105 | 0.4 | 0.042 | 0.3 | 0.35 | NEMSOK - Object Layer Attributes #1, Označení: VZT; Object Layer Attributes #1, Vnější průměr: 1010431516015xxxxxxx0
VZT | Půdorys 1.NP | Betonářské práce | 1452SVý1096221141 | m3 | Stěnový výklenek | NEW | 0.096 | 0.4 | 0.038 | 0.35 | 0.35 | NEMSOK - Object Layer Attributes #1, Označení: VZT
Okenní otvor | Půdorys 1.NP | Zateplovací systémy | 1452Okn0798445757 | m3 | Okenní otvor | NEW | 0.49 | 0.125 | 0.061 | 0.7 | 0.7
Okenní otvor | Půdorys 1.NP | Zateplovací systémy | 1452Okn0798446599 | m3 | Okenní otvor | NEW | 0.5 | 0.125 | 0.063 | 1 | 0.5
Dveřní otvor | Půdorys 1.NP | Betonářské práce | 1452Dve0798446357 | m3 | Dveřní otvor | NEW | 2.424 | 0.125 | 0.303 | 2.02 | 1.2 | NEMSOK - Object Layer Attributes #1, Směr otevírání dveří: L
Dveřní otvor | Půdorys 1.NP | Betonářské práce | 1452Dve0798446440 | m3 | Dveřní otvor | NEW | 2.424 | 0.125 | 0.303 | 2.02 | 1.2 | NEMSOK - Object Layer Attributes #1, Směr otevírání dveří: L
Dveřní otvor | Půdorys 1.NP | Betonářské práce | 1452Dve1096101417 | m3 | Dveřní otvor | NEW | 2.424 | 0.125 | 0.303 | 2.02 | 1.2 | NEMSOK - Object Layer Attributes #1, Směr otevírání dveří: P
Dveřní otvor | Půdorys 1.NP | Betonářské práce | 1452Dve1096101489 | m3 | Dveřní otvor | NEW | 2.424 | 0.125 | 0.303 | 2.02 | 1.2 | NEMSOK - Object Layer Attributes #1, Směr otevírání dveří: P
Dveřní otvor | Půdorys 1.NP | Betonářské práce | 1452Dve1096101550 | m3 | Dveřní otvor | NEW | 2.02 | 0.125 | 0.253 | 2.02 | 1 | NEMSOK - Object Layer Attributes #1, Směr otevírání dveří: L
Okenní otvor | Půdorys 1.NP | Zateplovací systémy | 1452Okn0798447102 | m3 | Okenní otvor | NEW | 0.72 | 0.125 | 0.09 | 1.2 | 0.6
Okenní otvor | Půdorys 1.NP | Zateplovací systémy | 1452Okn0798446984 | m3 | Okenní otvor | NEW | 0.54 | 0.125 | 0.068 | 1.2 | 0.45
Okenní otvor | Půdorys 1.NP | Zateplovací systémy | 1452Okn0798447061 | m3 | Okenní otvor | NEW | 0.54 | 0.125 | 0.068 | 1.2 | 0.45
Okenní otvor | Půdorys 1.NP | Zateplovací systémy | 1452Okn0798447144 | m3 | Okenní otvor | NEW | 0.5 | 0.125 | 0.062 | 1 | 0.5
Dveřní otvor | Půdorys 1.NP | Betonářské práce | 1452Dve0798447777 | m3 | Dveřní otvor | NEW | 1.818 | 0.125 | 0.227 | 2.02 | 0.9 | NEMSOK - Object Layer Attributes #1, Směr otevírání dveří: P
Dveřní otvor | Půdorys 1.NP | Betonářské práce | 1452Dve0798448108 | m2 | Dveřní otvor | NEW | 1.616 | 0.1 | 0.162 | 2.02 | 0.8 | NEMSOK - Object Layer Attributes #1, Směr otevírání dveří: P
Dveřní otvor | Půdorys 1.NP | Betonářské práce | 1452Dve0798448051 | m2 | Dveřní otvor | NEW | 1.616 | 0.1 | 0.162 | 2.02 | 0.8 | NEMSOK - Object Layer Attributes #1, Směr otevírání dveří: L
Dveřní otvor | Půdorys 1.NP | Betonářské práce | 1452Dve0798447349 | m2 | Dveřní otvor | NEW | 1.818 | 0.15 | 0.273 | 2.02 | 0.9 | NEMSOK - Object Layer Attributes #1, Směr otevírání dveří: L
Dveřní otvor | Půdorys 1.NP | Betonářské práce | 1452Dve0798447406 | m2 | Dveřní otvor | NEW | 1.818 | 0.15 | 0.273 | 2.02 | 0.9 | NEMSOK - Object Layer Attributes #1, Směr otevírání dveří: P
Dveřní otvor | Půdorys 1.NP | Betonářské práce | 1452Dve1096101334 | m2 | Dveřní otvor | EXISTING | 1.52 | 0.032 | 0.049 | 2 | 0.76 | NEMSOK - Object Layer Attributes #1, Směr otevírání dveří: L
Dveřní otvor | Půdorys 1.NP | Betonářské práce | 1452Dve1096101346 | m2 | Dveřní otvor | EXISTING | 1.52 | 0.032 | 0.049 | 2 | 0.76 | NEMSOK - Object Layer Attributes #1, Směr otevírání dveří: P
Dveřní otvor | Půdorys 1.NP | Betonářské práce | 1452Dve0798448273 | m2 | Dveřní otvor | EXISTING | 1.52 | 0.032 | 0.049 | 2 | 0.76 | NEMSOK - Object Layer Attributes #1, Směr otevírání dveří: L
Okenní otvor | Půdorys 1.NP | Zateplovací systémy | 1452Okn1096101684 | m3 | Okenní otvor | NEW | 0.5 | 0.125 | 0.063 | 1 | 0.5
Dveřní otvor | Půdorys 1.NP | Betonářské práce | 1452Dve1096104635 | m2 | Dveřní otvor | NEW | 2.02 | 0.15 | 0.303 | 2.02 | 1 | NEMSOK - Object Layer Attributes #1, Směr otevírání dveří: L
Dveřní otvor | Půdorys 1.NP | Betonářské práce | 1452Dve1096102778 | m2 | Dveřní otvor | NEW | 2.02 | 0.15 | 0.303 | 2.02 | 1 | NEMSOK - Object Layer Attributes #1, Směr otevírání dveří: P
Okenní otvor | Půdorys 1.NP | Zateplovací systémy | 1452Okn1096102968 | m3 | Okenní otvor | NEW | 0.5 | 0.125 | 0.062 | 1 | 0.5
Dveřní otvor | Půdorys 1.NP | Betonářské práce | 1452Dve1096103450 | m2 | Dveřní otvor | NEW | 2.02 | 0.15 | 0.303 | 2.02 | 1 | NEMSOK - Object Layer Attributes #1, Směr otevírání dveří: L
Dveřní otvor | Půdorys 1.NP | Betonářské práce | 1452Dve1096104078 | m3 | Dveřní otvor | NEW | 2.02 | 0.125 | 0.253 | 2.02 | 1 | NEMSOK - Object Layer Attributes #1, Směr otevírání dveří: L
Dveřní otvor | Půdorys 1.NP | Betonářské práce | 1452Dve1096104207 | m2 | Dveřní otvor | NEW | 2.02 | 0.15 | 0.303 | 2.02 | 1 | NEMSOK - Object Layer Attributes #1, Směr otevírání dveří: P
Dveřní otvor | Půdorys 1.NP | Betonářské práce | 1452Dve1096112889 | m2 | Dveřní otvor | NEW | 2.02 | 0.15 | 0.303 | 2.02 | 1 | NEMSOK - Object Layer Attributes #1, Směr otevírání dveří: P
Dveřní otvor | Půdorys 1.NP | Betonářské práce | 1452Dve1096113008 | m2 | Dveřní otvor | NEW | 2.02 | 0.15 | 0.303 | 2.02 | 1 | NEMSOK - Object Layer Attributes #1, Směr otevírání dveří: P
CHL | Půdorys 1.NP | Suché stavební práce | 1452SVý1096221373 | m3 | Stěna | NEW | 0.03 | 0.125 | 0.004 | 0.15 | 0.2 | NEMSOK - Object Layer Attributes #1, Označení: CHL; Object Layer Attributes #1, Podlaží: 1.NP; Object Layer Attributes #1, 2D interakce: yes; Object Layer Attributes #1, Staticky nosná konstrukce: no; Object Layer Attributes #1, Požární odolnost: EI 60
Okenní otvor | Půdorys 1.NP | Zateplovací systémy | 1452Okn1096104417 | m3 | Okenní otvor | NEW | 0.4 | 0.125 | 0.05 | 1 | 0.4
Dveřní otvor | Půdorys 1.NP | Betonářské práce | 1452Dve1096105654 | m3 | Dveřní otvor | NEW | 2.691 | 0.5 | 1.346 | 2.07 | 1.3 | NEMSOK - Object Layer Attributes #1, Směr otevírání dveří: -
Dveřní otvor | Půdorys 1.NP | Betonářské práce | 1452Dve1096105653 | m3 | Dveřní otvor | NEW | 2.691 | 0.5 | 1.346 | 2.07 | 1.3 | NEMSOK - Object Layer Attributes #1, Směr otevírání dveří: -
Dveřní otvor | Půdorys 1.NP | Betonářské práce | 1452Dve0798428112 | m2 | Dveřní otvor | NEW | 5.225 | 0.6 | 0.522 | 2.75 | 1.9 | NEMSOK - Object Layer Attributes #1, Směr otevírání dveří: -; Object Layer Attributes #2, Status: Nový; Object Layer Attributes #2, Práce: Betonářské práce; Object Layer Attributes #2, Allright_Stavebni_dil_ID: 1452Dve1096105452; Object Layer Attributes #2, Jednotka: m3; Object Layer Attributes #2, Název_objektu: Dveřní otvor; Object Layer Attributes #2, Směr otevírání dveří: -
Dveřní otvor | Půdorys 1.NP | Betonářské práce | 1452Dve1096118351 | m3 | Dveřní otvor | NEW | 1.616 | 0.125 | 0.202 | 2.02 | 0.8 | NEMSOK - Object Layer Attributes #1, Směr otevírání dveří: L
Dveřní otvor | Půdorys 1.NP | Betonářské práce | 1452Dve1096112306 | m3 | Dveřní otvor | NEW | 6.6 | 0.125 | 0.825 | 2.2 | 3 | NEMSOK - Object Layer Attributes #1, Směr otevírání dveří: -
ZTI | Půdorys 1.NP | Betonářské práce | 1452SVý1096221035 | m3 | Stěnový výklenek | NEW | 0.004 | 0.125 | 0 | 0.07 | 0.07 | NEMSOK - Object Layer Attributes #1, Označení: ZTI
ZTI | Půdorys 1.NP | Betonářské práce | 1452SVý1096221003 | m3 | Stěnový výklenek | NEW | 0.03 | 0.125 | 0.004 | 0.11 | 0.275 | NEMSOK - Object Layer Attributes #1, Označení: ZTI
Dveřní otvor | Půdorys 1.NP | Betonářské práce | 1452Dve0798431920 | m3 | Dveřní otvor | NEW | 3.45 | 0.125 | 0.431 | 2.3 | 1.5 | NEMSOK - Object Layer Attributes #1, Směr otevírání dveří: -
UT | Půdorys 1.NP | Betonářské práce | 1452SVý1096221787 | m3 | Stěnový výklenek | NEW | 0.034 | 0.12 | 0.004 | 0.12 | 0.28 | NEMSOK - Object Layer Attributes #1, Označení: UT
Okenní otvor | Půdorys 1.NP | Zateplovací systémy | 1452Okn1096112216 | m3 | Okenní otvor | NEW | 0.16 | 0.125 | 0.02 | 0.4 | 0.4
Dveřní otvor | Půdorys 1.NP | Betonářské práce | 1452Dve0798442059 | m3 | Dveřní otvor | NEW | 5.25 | 0.125 | 0.656 | 3 | 1.75 | NEMSOK - Object Layer Attributes #1, Směr otevírání dveří: -
Dveřní otvor | Půdorys 1.NP | Betonářské práce | 1452Dve1096110534 | m3 | Dveřní otvor | NEW | 1.414 | 0.125 | 0.177 | 2.02 | 0.7 | NEMSOK - Object Layer Attributes #1, Směr otevírání dveří: L
Dveřní otvor | Půdorys 1.NP | Betonářské práce | 1452Dve1096110647 | m3 | Dveřní otvor | NEW | 1.414 | 0.125 | 0.177 | 2.02 | 0.7 | NEMSOK - Object Layer Attributes #1, Směr otevírání dveří: P
Dveřní otvor | Půdorys 1.NP | Betonářské práce | 1452Dve0798444824 | m3 | Dveřní otvor | NEW | 9.765 | 0.4 | 3.906 | 3.15 | 3.1 | NEMSOK - Object Layer Attributes #1, Směr otevírání dveří: -
Dveřní otvor | Půdorys 1.NP | Betonářské práce | 1452Dve1096134954 | m3 | Dveřní otvor | NEW | 5.13 | 0.4 | 2.052 | 2.85 | 1.8 | NEMSOK - Object Layer Attributes #1, Směr otevírání dveří: -
ZTI | Půdorys 1.NP | Betonářské práce | 1452SVý1096221077 | m2 | Stěnový výklenek | NEW | 0.031 | 0.12 | 0.004 | 0.2 | 0.2 | NEMSOK - Object Layer Attributes #1, Označení: ZTI
Prostup stěnou | Půdorys 1.NP | Betonářské práce | 1452SVý1096221734 | m2 | Stěnový výklenek | NEW | 0.034 | 0.12 | 0.004 | 0.12 | 0.28
Dveřní otvor | Půdorys 1.NP | Betonářské práce | 1452Dve1096113373 | m3 | Dveřní otvor | NEW | 2.424 | 0.125 | 0.303 | 2.02 | 1.2 | NEMSOK - Object Layer Attributes #1, Směr otevírání dveří: P
Dveřní otvor | Půdorys 1.NP | Betonářské práce | 1452Dve1096113419 | m3 | Dveřní otvor | NEW | 2.424 | 0.125 | 0.303 | 2.02 | 1.2 | NEMSOK - Object Layer Attributes #1, Směr otevírání dveří: P
Dveřní otvor | Půdorys 1.NP | Betonářské práce | 1452Dve1096116324 | m3 | Dveřní otvor | NEW | 2.424 | 0.125 | 0.303 | 2.02 | 1.2 | NEMSOK - Object Layer Attributes #1, Směr otevírání dveří: P
Okenní otvor | Půdorys 1.NP | Zateplovací systémy | 1452Okn1096116836 | m3 | Okenní otvor | NEW | 0.5 | 0.125 | 0.063 | 1 | 0.5
Dveřní otvor | Půdorys 1.NP | Betonářské práce | 1452Dve1096113724 | m3 | Dveřní otvor | NEW | 1.616 | 0.125 | 0.202 | 2.02 | 0.8 | NEMSOK - Object Layer Attributes #1, Směr otevírání dveří: L
Dveřní otvor | Půdorys 1.NP | Betonářské práce | 1452Dve1096113643 | m3 | Dveřní otvor | NEW | 1.616 | 0.125 | 0.202 | 2.02 | 0.8 | NEMSOK - Object Layer Attributes #1, Směr otevírání dveří: P
Dveřní otvor | Půdorys 1.NP | Betonářské práce | 1452Dve1096114038 | m2 | Dveřní otvor | NEW | 1.616 | 0.1 | 0.162 | 2.02 | 0.8 | NEMSOK - Object Layer Attributes #1, Směr otevírání dveří: P
Dveřní otvor | Půdorys 1.NP | Betonářské práce | 1452Dve1096114145 | m2 | Dveřní otvor | NEW | 1.616 | 0.1 | 0.162 | 2.02 | 0.8 | NEMSOK - Object Layer Attributes #1, Směr otevírání dveří: L
Dveřní otvor | Půdorys 1.NP | Betonářské práce | 1452Dve0798433040 | m3 | Dveřní otvor | NEW | 1.616 | 0.125 | 0.202 | 2.02 | 0.8 | NEMSOK - Object Layer Attributes #1, Směr otevírání dveří: L
Dveřní otvor | Půdorys 1.NP | Betonářské práce | 1452Dve0798433099 | m3 | Dveřní otvor | NEW | 1.818 | 0.125 | 0.227 | 2.02 | 0.9 | NEMSOK - Object Layer Attributes #1, Směr otevírání dveří: L
Dveřní otvor | Půdorys 1.NP | Betonářské práce | 1452Dve1096114202 | m2 | Dveřní otvor | NEW | 1.616 | 0.1 | 0.162 | 2.02 | 0.8 | NEMSOK - Object Layer Attributes #1, Směr otevírání dveří: L
Dveřní otvor | Půdorys 1.NP | Betonářské práce | 1452Dve1096114269 | m2 | Dveřní otvor | NEW | 1.616 | 0.1 | 0.162 | 2.02 | 0.8 | NEMSOK - Object Layer Attributes #1, Směr otevírání dveří: L
Dveřní otvor | Půdorys 1.NP | Betonářské práce | 1452Dve1096115260 | m3 | Dveřní otvor | NEW | 1.616 | 0.125 | 0.202 | 2.02 | 0.8 | NEMSOK - Object Layer Attributes #1, Směr otevírání dveří: P
Dveřní otvor | Půdorys 1.NP | Betonářské práce | 1452Dve0798433509 | m3 | Dveřní otvor | NEW | 2.02 | 0.125 | 0.253 | 2.02 | 1 | NEMSOK - Object Layer Attributes #1, Směr otevírání dveří: P
Okenní otvor | Půdorys 1.NP | Zateplovací systémy | 1452Okn1096116647 | m3 | Okenní otvor | NEW | 0.5 | 0.125 | 0.063 | 1 | 0.5
Dveřní otvor | Půdorys 1.NP | Betonářské práce | 1452Dve1096116302 | m3 | Dveřní otvor | NEW | 2.424 | 0.125 | 0.303 | 2.02 | 1.2 | NEMSOK - Object Layer Attributes #1, Směr otevírání dveří: P
Dveřní otvor | Půdorys 1.NP | Betonářské práce | 1452Dve1096116280 | m3 | Dveřní otvor | NEW | 2.424 | 0.125 | 0.303 | 2.02 | 1.2 | NEMSOK - Object Layer Attributes #1, Směr otevírání dveří: P
Okenní otvor | Půdorys 1.NP | Zateplovací systémy | 1452Okn1096116483 | m2 | Okenní otvor | NEW | 3.225 | 0.12 | 0.387 | 2.15 | 1.5
Okenní otvor | Půdorys 1.NP | Zateplovací systémy | 1452Okn1096116542 | m2 | Okenní otvor | NEW | 3.225 | 0.12 | 0.387 | 2.15 | 1.5
Okenní otvor | Půdorys 1.NP | Zateplovací systémy | 1452Okn1096116553 | m2 | Okenní otvor | NEW | 3.225 | 0.12 | 0.387 | 2.15 | 1.5
Okenní otvor | Půdorys 1.NP | Zateplovací systémy | 1452Okn1096116947 | m3 | Okenní otvor | NEW | 0.5 | 0.125 | 0.063 | 1 | 0.5
Okenní otvor | Půdorys 1.NP | Zateplovací systémy | 1452Okn1096117592 | m2 | Okenní otvor | NEW | 2.75 | 0.125 | 0.344 | 1.1 | 2.5
Dveřní otvor | Půdorys 1.NP | Betonářské práce | 1452Dve1096117403 | m2 | Dveřní otvor | NEW | 1.616 | 0.125 | 0.202 | 2.02 | 0.8 | NEMSOK - Object Layer Attributes #1, Směr otevírání dveří: P
Dveřní otvor | Půdorys 1.NP | Betonářské práce | 1452Dve1096117477 | m2 | Dveřní otvor | NEW | 1.616 | 0.125 | 0.202 | 2.02 | 0.8 | NEMSOK - Object Layer Attributes #1, Směr otevírání dveří: P
Dveřní otvor | Půdorys 1.NP | Betonářské práce | 1452Dve1096104127 | m3 | Dveřní otvor | NEW | 2.424 | 0.125 | 0.303 | 2.02 | 1.2 | NEMSOK - Object Layer Attributes #1, Směr otevírání dveří: P
Dveřní otvor | Půdorys 1.NP | Betonářské práce | 1452Dve1096103561 | m3 | Dveřní otvor | NEW | 2.424 | 0.125 | 0.303 | 2.02 | 1.2 | NEMSOK - Object Layer Attributes #1, Směr otevírání dveří: L
Dveřní otvor | Půdorys 1.NP | Betonářské práce | 1452Dve1096102434 | m3 | Dveřní otvor | NEW | 2.424 | 0.125 | 0.303 | 2.02 | 1.2 | NEMSOK - Object Layer Attributes #1, Směr otevírání dveří: P
Dveřní otvor | Půdorys 1.NP | Betonářské práce | 1452Dve1096102388 | m3 | Dveřní otvor | NEW | 2.424 | 0.125 | 0.303 | 2.02 | 1.2 | NEMSOK - Object Layer Attributes #1, Směr otevírání dveří: L
Dveřní otvor | Půdorys 1.NP | Betonářské práce | 1452Dve1096101750 | m3 | Dveřní otvor | NEW | 1.35 | 0.125 | 0.169 | 2.25 | 0.6 | NEMSOK - Object Layer Attributes #1, Směr otevírání dveří: -
Dveřní otvor | Půdorys 1.NP | Betonářské práce | 1452Dve1096101756 | m3 | Dveřní otvor | NEW | 1.616 | 0.125 | 0.202 | 2.02 | 0.8 | NEMSOK - Object Layer Attributes #1, Směr otevírání dveří: L
Dveřní otvor | Půdorys 1.NP | Betonářské práce | 1452Dve1096102183 | m3 | Dveřní otvor | NEW | 2.424 | 0.125 | 0.303 | 2.02 | 1.2 | NEMSOK - Object Layer Attributes #1, Směr otevírání dveří: P
Dveřní otvor | Půdorys 1.NP | Betonářské práce | 1452Dve1096103028 | m3 | Dveřní otvor | NEW | 2.424 | 0.125 | 0.303 | 2.02 | 1.2 | NEMSOK - Object Layer Attributes #1, Směr otevírání dveří: P
Dveřní otvor | Půdorys 1.NP | Betonářské práce | 1452Dve1096103074 | m3 | Dveřní otvor | NEW | 1.616 | 0.125 | 0.202 | 2.02 | 0.8 | NEMSOK - Object Layer Attributes #1, Směr otevírání dveří: P
Dveřní otvor | Půdorys 1.NP | Betonářské práce | 1452Dve1096103181 | m3 | Dveřní otvor | NEW | 2.424 | 0.125 | 0.303 | 2.02 | 1.2 | NEMSOK - Object Layer Attributes #1, Směr otevírání dveří: P
Dveřní otvor | Půdorys 1.NP | Betonářské práce | 1452Dve1096117801 | m3 | Dveřní otvor | NEW | 2.424 | 0.125 | 0.303 | 2.02 | 1.2 | NEMSOK - Object Layer Attributes #1, Směr otevírání dveří: L
Dveřní otvor | Půdorys 1.NP | Betonářské práce | 1452Dve1096118408 | m3 | Dveřní otvor | NEW | 1.616 | 0.125 | 0.202 | 2.02 | 0.8 | NEMSOK - Object Layer Attributes #1, Směr otevírání dveří: L
Dveřní otvor | Půdorys 1.NP | Betonářské práce | 1452Dve1096118446 | m3 | Dveřní otvor | NEW | 1.616 | 0.125 | 0.202 | 2.02 | 0.8 | NEMSOK - Object Layer Attributes #1, Směr otevírání dveří: L
Dveřní otvor | Půdorys 1.NP | Betonářské práce | 1452Dve1096118303 | m2 | Dveřní otvor | NEW | 1.616 | 0.1 | 0.162 | 2.02 | 0.8 | NEMSOK - Object Layer Attributes #1, Směr otevírání dveří: L
Dveřní otvor | Půdorys 1.NP | Betonářské práce | 1452Dve1096112796 | m2 | Dveřní otvor | NEW | 2.02 | 0.125 | 0.253 | 2.02 | 1 | NEMSOK - Object Layer Attributes #1, Směr otevírání dveří: L
Dveřní otvor | Půdorys 1.NP | Betonářské práce | 1452Dve1096118255 | m2 | Dveřní otvor | NEW | 1.616 | 0.1 | 0.162 | 2.02 | 0.8 | NEMSOK - Object Layer Attributes #1, Směr otevírání dveří: L
Dveřní otvor | Půdorys 1.NP | Betonářské práce | 1452Dve1096118536 | m2 | Dveřní otvor | NEW | 1.616 | 0.1 | 0.162 | 2.02 | 0.8 | NEMSOK - Object Layer Attributes #1, Směr otevírání dveří: L
Dveřní otvor | Půdorys 1.NP | Betonářské práce | 1452Dve1096119070 | m3 | Dveřní otvor | NEW | 2.813 | 0.125 | 0.352 | 2.25 | 1.25 | NEMSOK - Object Layer Attributes #1, Směr otevírání dveří: -
Dveřní otvor | Půdorys 1.NP | Betonářské práce | 1452Dve1096134272 | m3 | Dveřní otvor | NEW | 2.544 | 0.125 | 0.318 | 2.12 | 1.2 | NEMSOK - Object Layer Attributes #1, Směr otevírání dveří: -
Dveřní otvor | Půdorys 1.NP | Betonářské práce | 1452Dve1096220448 | m3 | Dveřní otvor | NEW | 2.12 | 0.125 | 0.265 | 2.12 | 1 | NEMSOK - Object Layer Attributes #1, Směr otevírání dveří: -
Okenní otvor | Půdorys 1.NP | Zateplovací systémy | 1452Okn1096220496 | m3 | Okenní otvor | NEW | 0.72 | 0.125 | 0.09 | 1.2 | 0.6
Dveřní otvor | Půdorys 1.NP | Betonářské práce | 1452Dve1096119192 | m2 | Dveřní otvor | NEW | 3.74 | 0.15 | 0.561 | 2.2 | 1.7 | NEMSOK - Object Layer Attributes #1, Směr otevírání dveří: -
Dveřní otvor | Půdorys 1.NP | Betonářské práce | 1452Dve0798424495 | m3 | Dveřní otvor | NEW | 3.131 | 0.125 | 0.391 | 2.02 | 1.55 | NEMSOK - Object Layer Attributes #1, Směr otevírání dveří: -
VZT | Půdorys 1.NP | Betonářské práce | 1452SVý1096220799 | m3 | Stěnový výklenek | NEW | 0.031 | 0.125 | 0.004 | 0.2 | 0.2 | NEMSOK - Object Layer Attributes #1, Označení: VZT
Dveřní otvor | Půdorys 1.NP | Betonářské práce | 1452Dve1096131851 | m3 | Dveřní otvor | NEW | 2.07 | 0.125 | 0.259 | 2.3 | 0.9 | NEMSOK - Object Layer Attributes #1, Směr otevírání dveří: -
Okenní otvor | Půdorys 1.NP | Zateplovací systémy | 1452Okn1096132840 | m3 | Okenní otvor | NEW | 1.008 | 0.32 | 0.323 | 2.1 | 0.48
Dveřní otvor | Půdorys 1.NP | Betonářské práce | 1452Dve1096132799 | m3 | Dveřní otvor | NEW | 3.315 | 0.32 | 1.061 | 3.25 | 1.02 | NEMSOK - Object Layer Attributes #1, Směr otevírání dveří: -
Dveřní otvor | Půdorys 1.NP | Betonářské práce | 1452Dve1096132883 | m3 | Dveřní otvor | NEW | 1.056 | 0.32 | 0.338 | 2.2 | 0.48 | NEMSOK - Object Layer Attributes #1, Směr otevírání dveří: -
ZTI | Půdorys 1.NP | Suché stavební práce | 1452SVý1096220965 | m3 | Stěnový výklenek |  | 0.03 | 0.32 | 0.01 | 0.11 | 0.275 | NEMSOK - Object Layer Attributes #1, Označení: ZTI; Object Layer Attributes #1, Vnější průměr: 1010431516015xxxxxxx0
ZTI HL.100 | Půdorys 1.NP | Suché stavební práce | 1452SNi1096221192 | m3 | Stěnová nika |  | 0.128 | 0.1 | 0.013 | 0.85 | 0.15 | NEMSOK - Object Layer Attributes #1, Označení: ZTI HL.100; Object Layer Attributes #1, Vnější průměr: 1010431516015xxxxxxx0
ZTI HL.60 | Půdorys 1.NP | Suché stavební práce | 1452SVý1096221711 | m3 | Stěnový výklenek |  | 0.137 | 0.06 | 0.008 | 2.28 | 0.06 | NEMSOK - Object Layer Attributes #1, Označení: ZTI HL.60; Object Layer Attributes #1, Vnější průměr: 1010431516015xxxxxxx0
ZTI HL.60 | Půdorys 1.NP | Suché stavební práce | 1452SVý1096221637 | m3 | Stěnový výklenek |  | 0.137 | 0.06 | 0.008 | 2.28 | 0.06 | NEMSOK - Object Layer Attributes #1, Označení: ZTI HL.60; Object Layer Attributes #1, Vnější průměr: 1010431516015xxxxxxx0
Dveřní otvor | Půdorys 1.NP | Betonářské práce | 1452Dve0798443603 | m3 | Dveřní otvor | NEW | 1.818 | 0.4 | 0.727 | 2.02 | 0.9 | NEMSOK - Object Layer Attributes #1, Směr otevírání dveří: -
Dveřní otvor | Půdorys 1.NP | Betonářské práce | 1452Dve0798442706 | m3 | Dveřní otvor | NEW | 8.19 | 0.4 | 3.276 | 3.15 | 2.6 | NEMSOK - Object Layer Attributes #1, Směr otevírání dveří: -
ZTI | Půdorys 1.NP | Betonářské práce | 1452SVý1096221230 | m3 | Stěnový výklenek | NEW | 0.052 | 0.4 | 0.021 | 0.15 | 0.35 | NEMSOK - Object Layer Attributes #1, Označení: ZTI
UT | Půdorys 1.NP | Betonářské práce | 1452SVý1096221269 | m3 | Stěnový výklenek | NEW | 0.045 | 0.4 | 0.018 | 0.15 | 0.3 | NEMSOK - Object Layer Attributes #1, Označení: UT
Okenní otvor | Půdorys 1.NP | Zateplovací systémy | 1452Okn0000004712 | m3 | Okenní otvor | NEW | 2.25 | 0.42 | 0.72 | 1.5 | 1.5 | NEMSOK - Object Layer Attributes #2, Status: Nový; Object Layer Attributes #2, Práce: Zateplovací systémy; Object Layer Attributes #2, Allright_Stavebni_dil_ID: 1452Okn1096106639; Object Layer Attributes #2, Jednotka: m2; Object Layer Attributes #2, Název_objektu: Okenní otvor
Okenní otvor | Půdorys 1.NP | Zateplovací systémy | 1452Okn0000004648 | m3 | Okenní otvor | NEW | 2.25 | 0.42 | 0.72 | 1.5 | 1.5 | NEMSOK - Object Layer Attributes #2, Status: Nový; Object Layer Attributes #2, Práce: Zateplovací systémy; Object Layer Attributes #2, Allright_Stavebni_dil_ID: 1452Okn1096106629; Object Layer Attributes #2, Jednotka: m2; Object Layer Attributes #2, Název_objektu: Okenní otvor
Okenní otvor | Půdorys 1.NP | Zateplovací systémy | 1452Okn0000004680 | m3 | Okenní otvor | NEW | 2.25 | 0.42 | 0.72 | 1.5 | 1.5 | NEMSOK - Object Layer Attributes #2, Status: Nový; Object Layer Attributes #2, Práce: Zateplovací systémy; Object Layer Attributes #2, Allright_Stavebni_dil_ID: 1452Okn1096106588; Object Layer Attributes #2, Jednotka: m2; Object Layer Attributes #2, Název_objektu: Okenní otvor
Dveřní otvor | Půdorys 1.NP | Betonářské práce | 1452Dve0798424558 | m3 | Dveřní otvor | NEW | 2.616 | 0.55 | 1.177 | 2.18 | 1.2 | NEMSOK - Object Layer Attributes #1, Směr otevírání dveří: P; Object Layer Attributes #2, Status: Nový; Object Layer Attributes #2, Práce: Betonářské práce; Object Layer Attributes #2, Allright_Stavebni_dil_ID: 1452Dve1096106431; Object Layer Attributes #2, Jednotka: m2; Object Layer Attributes #2, Název_objektu: Dveřní otvor; Object Layer Attributes #2, Směr otevírání dveří: P
CHL | Půdorys 1.NP | Suché stavební práce | 1452SVý1096220569 | m3 | Stěnový výklenek |  | 0.015 | 0.55 | 0.008 | 0.15 | 0.1 | NEMSOK - Object Layer Attributes #1, Označení: CHL; Object Layer Attributes #1, Vnější průměr: 1010431516015xxxxxxx0
Okenní otvor | Půdorys 1.NP | Zateplovací systémy | 1452Okn1096134476 | m3 | Okenní otvor | NEW | 3.06 | 0.32 | 0.979 | 2.04 | 1.5
Okenní otvor | Půdorys 1.NP | Zateplovací systémy | 1452Okn1096134475 | m3 | Okenní otvor | NEW | 3.06 | 0.32 | 0.979 | 2.04 | 1.5
ZTI | Půdorys 1.NP | Betonářské práce | 1452SVý1096220814 | m3 | Stěnový výklenek | NEW | 0.008 | 0.32 | 0.003 | 0.1 | 0.1 | NEMSOK - Object Layer Attributes #1, Označení: ZTI
Dveřní otvor | Půdorys 1.NP | Betonářské práce | 1452Dve1096134636 | m3 | Dveřní otvor | NEW | 4.605 | 0.32 | 1.474 | 3.07 | 1.5 | NEMSOK - Object Layer Attributes #1, Směr otevírání dveří: -
Stěnová nika | Půdorys 1.NP | Betonářské práce | 1452SNi1096221814 | m3 | Stěnová nika | NEW | 0.025 | 0.32 | 0.008 | 0.25 | 0.1
Dveřní otvor | Půdorys 1.NP | Betonářské práce | 1452Dve1096130696 | m2 | Dveřní otvor | NEW | 2.875 | 0.125 | 0.359 | 2.3 | 1.25 | NEMSOK - Object Layer Attributes #1, Směr otevírání dveří: -
Prostup deskou | Půdorys 1.NP | Zámečnické práce | 1452DOt1096221346 | m2 | Otvor v desce | NEW | 0.01 | 0.08 | 0 | 0.03 | 0.13
VZT | Půdorys 1.NP | Betonářské práce | 1452SVý1096220686 | m3 | Stěnový výklenek | NEW | 0.053 | 0.125 | 0.007 | 0.26 | 0.26 | NEMSOK - Object Layer Attributes #1, Označení: VZT
Dveřní otvor | Půdorys 1.NP | Betonářské práce | 1452Dve0798430865 | m3 | Dveřní otvor | NEW | 1.908 | 0.125 | 0.238 | 2.12 | 0.9 | NEMSOK - Object Layer Attributes #1, Směr otevírání dveří: -
Okenní otvor | Půdorys 1.NP | Zateplovací systémy | 1452Okn1096116014 | m3 | Okenní otvor | NEW | 0.09 | 0.125 | 0.011 | 0.3 | 0.3
Dveřní otvor | Půdorys 1.NP | Betonářské práce | 1452Dve1096118717 | m3 | Dveřní otvor | NEW | 1.908 | 0.125 | 0.238 | 2.12 | 0.9 | NEMSOK - Object Layer Attributes #1, Směr otevírání dveří: -
VZT | Půdorys 1.NP | Betonářské práce | 1452SVý1096220655 | m3 | Stěnový výklenek | NEW | 0.053 | 0.125 | 0.007 | 0.26 | 0.26 | NEMSOK - Object Layer Attributes #1, Označení: VZT
Prostup deskou | Půdorys 1.NP | Betonářské práce | 1454DOt0000000900 | m3 | Otvor v desce | NEW | 0.1 | 0.5 | 0.025 | 0.25 | 0.2
Prostup deskou | Půdorys 1.NP | Betonářské práce | 1454DOt0000000849 | m3 | Otvor v desce | NEW | 0.35 | 0.7 | 0.087 | 0.25 | 0.5
Prostup deskou | Půdorys 1.NP | Betonářské práce | 1454DOt0000000919 | m3 | Otvor v desce | NEW | 0.6 | 1 | 0.15 | 0.25 | 0.6
Prostup deskou | Půdorys 1.NP | Betonářské práce | 1454DOt0000000921 | m3 | Otvor v desce | NEW | 0.275 | 0.5 | 0.069 | 0.25 | 0.55
Prostup deskou | Půdorys 1.NP | Betonářské práce | 1454DOt0000000858 | m3 | Otvor v desce | NEW | 0.81 | 2.7 | 0.203 | 0.25 | 0.3
Prostup deskou | Půdorys 1.NP | Betonářské práce | 1454DOt0000001587 | m3 | Otvor v desce | NEW | 0.07 | 0.2 | 0.007 | 0.1 | 0.35
Prostup deskou | Půdorys 1.NP | Betonářské práce | 1454DOt0000001589 | m3 | Otvor v desce | NEW | 0.01 | 0.1 | 0.001 | 0.1 | 0.1
Prostup deskou | Půdorys 1.NP | Betonářské práce | 1454DOt0000001585 | m3 | Otvor v desce | NEW | 0.27 | 0.9 | 0.027 | 0.1 | 0.3
Prostup deskou | Půdorys 1.NP | Betonářské práce | 1454DOt0000000542 | m3 | Otvor v desce | NEW | 0.18 | 0.45 | 0.045 | 0.25 | 0.4
Prostup deskou | Půdorys 1.NP | Betonářské práce | 1454DOt0000000568 | m3 | Otvor v desce | NEW | 0.18 | 0.45 | 0.045 | 0.25 | 0.4
Prostup deskou | Půdorys 1.NP | Betonářské práce | 1454DOt0000000503 | m3 | Otvor v desce | NEW | 0.26 | 0.4 | 0.065 | 0.25 | 0.65
Prostup deskou | Půdorys 1.NP | Betonářské práce | 1454DOt0000001608 | m3 | Otvor v desce | NEW | 0.065 | 0.1 | 0.016 | 0.25 | 0.65
Prostup deskou | Půdorys 1.NP | Betonářské práce | 1454DOt0000000878 | m3 | Otvor v desce | NEW | 0.14 | 0.7 | 0.035 | 0.25 | 0.2
Prostup deskou | Půdorys 1.NP | Betonářské práce | 1454DOt0000000880 | m3 | Otvor v desce | NEW | 0.385 | 0.7 | 0.096 | 0.25 | 0.55
Prostup deskou | Půdorys 1.NP | Betonářské práce | 1454DOt0000000890 | m3 | Otvor v desce | NEW | 0.1 | 0.5 | 0.025 | 0.25 | 0.2
Prostup deskou | Půdorys 1.NP | Betonářské práce | 1454DOt0000000884 | m3 | Otvor v desce | NEW | 0.21 | 1.05 | 0.053 | 0.25 | 0.2
Prostup deskou | Půdorys 1.NP | Betonářské práce | 1454DOt0000000882 | m3 | Otvor v desce | NEW | 2.992 | 1.05 | 0.748 | 0.25 | 2.85
Prostup deskou | Půdorys 1.NP | Betonářské práce | 1454DOt0000000906 | m3 | Otvor v desce | NEW | 0.3 | 0.6 | 0.075 | 0.25 | 0.5
Prostup deskou | Půdorys 1.NP | Betonářské práce | 1454DOt0000000910 | m3 | Otvor v desce | NEW | 0.27 | 0.3 | 0.067 | 0.25 | 0.9
Prostup deskou | Půdorys 1.NP | Betonářské práce | 1454DOt0000000471 | m3 | Otvor v desce | NEW | 0.249 | 0.83 | 0.062 | 0.25 | 0.3
Prostup deskou | Půdorys 1.NP | Betonářské práce | 1454DOt0000000466 | m3 | Otvor v desce | NEW | 0.24 | 0.3 | 0.06 | 0.25 | 0.8
Prostup deskou | Půdorys 1.NP | Betonářské práce | 1454DOt0000000508 | m3 | Otvor v desce | NEW | 0.44 | 1.1 | 0.11 | 0.25 | 0.4
Prostup deskou | Půdorys 1.NP | Betonářské práce | 1454DOt0000000498 | m3 | Otvor v desce | NEW | 0.72 | 0.8 | 0.18 | 0.25 | 0.9
Prostup deskou | Půdorys 1.NP | Betonářské práce | 1454DOt0000000537 | m3 | Otvor v desce | NEW | 0.44 | 1.1 | 0.11 | 0.25 | 0.4
Prostup deskou | Půdorys 1.NP | Betonářské práce | 1454DOt0000000493 | m3 | Otvor v desce | NEW | 0.114 | 0.4 | 0.028 | 0.25 | 0.285
Prostup deskou | Půdorys 1.NP | Betonářské práce | 1454DOt0000001719 | m3 | Otvor v desce | NEW | 0.018 | 0.118 | 0.004 | 0.25 | 0.15
Prostup deskou | Půdorys 1.NP | Betonářské práce | 1454DOt0000001724 | m3 | Otvor v desce | NEW | 0.018 | 0.118 | 0.004 | 0.25 | 0.15
Prostup deskou | Půdorys 1.NP | Betonářské práce | 1454DOt0000001729 | m3 | Otvor v desce | NEW | 0.018 | 0.118 | 0.004 | 0.25 | 0.15
Prostup deskou | Půdorys 1.NP | Betonářské práce | 1454DOt0000001739 | m3 | Otvor v desce | NEW | 0.018 | 0.118 | 0.004 | 0.25 | 0.15
Prostup deskou | Půdorys 1.NP | Betonářské práce | 1454DOt0000000841 | m3 | Otvor v desce | NEW | 0.385 | 0.7 | 0.096 | 0.25 | 0.55
Prostup deskou | Půdorys 1.NP | Betonářské práce | 1454DOt0000000843 | m3 | Otvor v desce | NEW | 0.25 | 0.5 | 0.062 | 0.25 | 0.5
Prostup deskou | Půdorys 1.NP | Betonářské práce | 1454DOt0000000847 | m3 | Otvor v desce | NEW | 0.22 | 0.4 | 0.055 | 0.25 | 0.55
Prostup deskou | Půdorys 1.NP | Betonářské práce | 1454DOt0000001160 | m3 | Otvor v desce | NEW | 0.09 | 0.45 | 0.023 | 0.25 | 0.2
Prostup deskou | Půdorys 1.NP | Betonářské práce | 1454DOt0000000845 | m3 | Otvor v desce | NEW | 0.16 | 0.4 | 0.04 | 0.25 | 0.4
Prostup deskou | Půdorys 1.NP | Betonářské práce | 1454DOt0000000834 | m3 | Otvor v desce | NEW | 0.3 | 0.5 | 0.075 | 0.25 | 0.6
Prostup deskou | Půdorys 1.NP | Betonářské práce | 1454DOt0000000832 | m3 | Otvor v desce | NEW | 0.237 | 0.5 | 0.059 | 0.25 | 0.475
Prostup deskou | Půdorys 1.NP | Betonářské práce | 1454DOt0000001734 | m3 | Otvor v desce | NEW | 0.018 | 0.118 | 0.004 | 0.25 | 0.15
Prostup deskou | Půdorys 1.NP | Betonářské práce | 1454DOt0000001823 | m3 | Otvor v desce | NEW | 0.018 | 0.118 | 0.004 | 0.2 | 0.15
Prostup deskou | Půdorys 1.NP | Betonářské práce | 1454DOt0000001828 | m3 | Otvor v desce | NEW | 0.018 | 0.118 | 0.004 | 0.2 | 0.15
Prostup deskou | Půdorys 1.NP | Betonářské práce | 1454DOt0000001833 | m3 | Otvor v desce | NEW | 0.018 | 0.118 | 0.004 | 0.2 | 0.15
Dveřní otvor | Půdorys 1.NP | Betonářské práce | 1464Dve1096312795 | m3 | Dveřní otvor | NEW | 3.45 | 0.125 | 0.431 | 2.3 | 1.5 | NEMSOK - Object Layer Attributes #1, Směr otevírání dveří: -
Dveřní otvor | Půdorys 1.NP | Betonářské práce | 1464Dve1096207911 | m3 | Dveřní otvor | NEW | 5.25 | 0.125 | 0.656 | 3 | 1.75 | NEMSOK - Object Layer Attributes #1, Směr otevírání dveří: -
Dveřní otvor | Půdorys 1.NP | Betonářské práce | 1464Dve1096208812 | m2 | Dveřní otvor | NEW | 3.22 | 0.15 | 0.483 | 2.3 | 1.4 | NEMSOK - Object Layer Attributes #1, Směr otevírání dveří: L
Dveřní otvor | Půdorys 1.NP | Betonářské práce | 1464Dve1096158281 | m3 | Dveřní otvor | NEW | 3.15 | 0.1 | 0.315 | 2.1 | 1.5 | NEMSOK - Object Layer Attributes #1, Směr otevírání dveří: -; Object Layer Attributes #1, Označení: Dveřní otvor
Dveřní otvor | Půdorys 1.NP | Betonářské práce | 1464Dve1096159790 | m3 | Dveřní otvor | NEW | 3.78 | 0.1 | 0.378 | 2.1 | 1.8 | NEMSOK - Object Layer Attributes #1, Směr otevírání dveří: -; Object Layer Attributes #1, Označení: Dveřní otvor
Dveřní otvor | Půdorys 1.NP | Betonářské práce | 1464Dve1096205266 | m3 | Dveřní otvor | NEW | 2.94 | 0.1 | 0.294 | 2.1 | 1.4 | NEMSOK - Object Layer Attributes #1, Směr otevírání dveří: P; Object Layer Attributes #1, Označení: Dveřní otvor
Dveřní otvor | Půdorys 1.NP | Betonářské práce | 1464Dve1096158255 | m3 | Dveřní otvor | NEW | 2.94 | 0.1 | 0.294 | 2.1 | 1.4 | NEMSOK - Object Layer Attributes #1, Směr otevírání dveří: P; Object Layer Attributes #1, Označení: Dveřní otvor
Dveřní otvor | Půdorys 1.NP | Betonářské práce | 1464Dve1096205654 | m3 | Dveřní otvor | NEW | 2.94 | 0.1 | 0.294 | 2.1 | 1.4 | NEMSOK - Object Layer Attributes #1, Směr otevírání dveří: P; Object Layer Attributes #1, Označení: Dveřní otvor
Dveřní otvor | Půdorys 1.NP | Betonářské práce | 1464Dve1096205775 | m3 | Dveřní otvor | NEW | 2.94 | 0.1 | 0.294 | 2.1 | 1.4 | NEMSOK - Object Layer Attributes #1, Směr otevírání dveří: P; Object Layer Attributes #1, Označení: Dveřní otvor
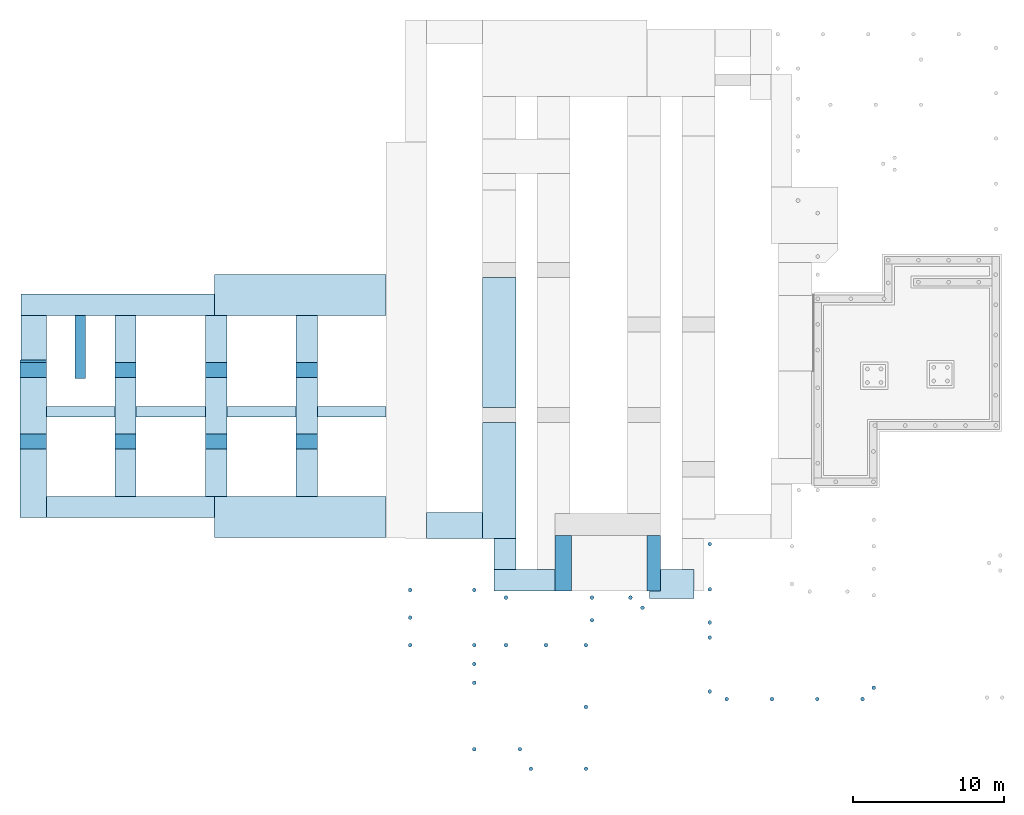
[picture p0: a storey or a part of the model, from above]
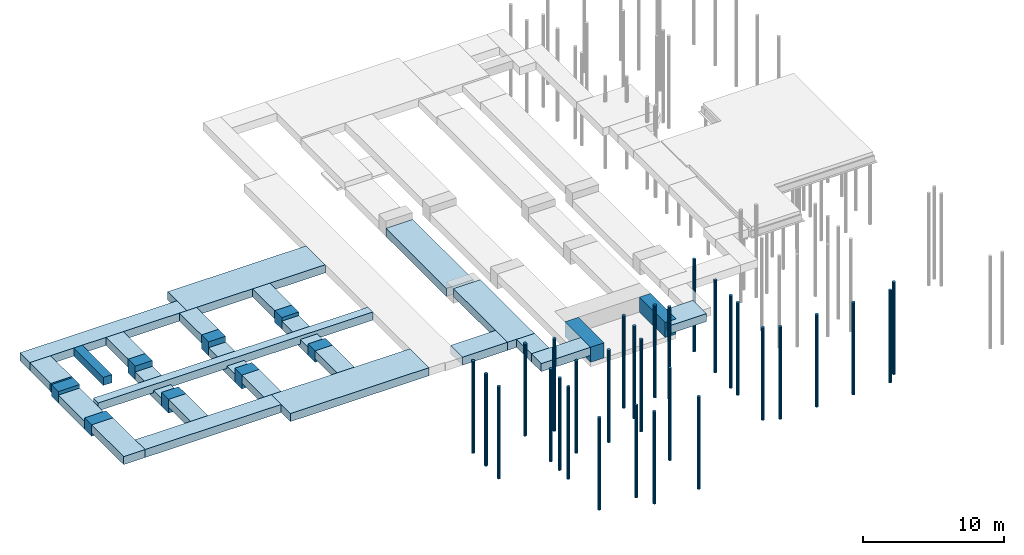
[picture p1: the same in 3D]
Properties of the parts of a building model (IFC4), part 16 of 45

# IfcOpeningElement: Opening (1638)
Name | In | Object Layer Attributes #1, Práce | Object Layer Attributes #1, Allright_Stavebni_dil_ID | Object Layer Attributes #1, Jednotka | Object Layer Attributes #1, Název_objektu | Status | Area (m2) | Depth (m) | Volume (m3) | Height (m) | Width (m)
Dveřní otvor | Půdorys 1.NP | Betonářské práce | 1464Dve1096205828 | m3 | Dveřní otvor | NEW | 2.94 | 0.1 | 0.294 | 2.1 | 1.4 | NEMSOK - Object Layer Attributes #1, Směr otevírání dveří: P; Object Layer Attributes #1, Označení: Dveřní otvor
Dveřní otvor | Půdorys 1.NP | Betonářské práce | 1464Dve1096206025 | m3 | Dveřní otvor | NEW | 2.94 | 0.1 | 0.294 | 2.1 | 1.4 | NEMSOK - Object Layer Attributes #1, Směr otevírání dveří: P; Object Layer Attributes #1, Označení: Dveřní otvor
Dveřní otvor | Půdorys 1.NP | Betonářské práce | 1464Dve1096207171 | m3 | Dveřní otvor | NEW | 1.89 | 0.1 | 0.189 | 2.1 | 0.9 | NEMSOK - Object Layer Attributes #1, Směr otevírání dveří: L; Object Layer Attributes #1, Označení: Dveřní otvor
Dveřní otvor | Půdorys 1.NP | Betonářské práce | 1464Dve1096207252 | m3 | Dveřní otvor | NEW | 1.89 | 0.1 | 0.189 | 2.1 | 0.9 | NEMSOK - Object Layer Attributes #1, Směr otevírání dveří: L; Object Layer Attributes #1, Označení: Dveřní otvor
Dveřní otvor | Půdorys 1.NP | Betonářské práce | 1464Dve1096207334 | m3 | Dveřní otvor | NEW | 1.89 | 0.1 | 0.189 | 2.1 | 0.9 | NEMSOK - Object Layer Attributes #1, Směr otevírání dveří: L; Object Layer Attributes #1, Označení: Dveřní otvor
Dveřní otvor | Půdorys 1.NP | Betonářské práce | 1464Dve1096207009 | m3 | Dveřní otvor | NEW | 1.89 | 0.1 | 0.189 | 2.1 | 0.9 | NEMSOK - Object Layer Attributes #1, Směr otevírání dveří: L; Object Layer Attributes #1, Označení: Dveřní otvor
Dveřní otvor | Půdorys 1.NP | Betonářské práce | 1464Dve1096325907 | m3 | Dveřní otvor | NEW | 5.13 | 0.4 | 2.052 | 2.85 | 1.8 | NEMSOK - Object Layer Attributes #1, Směr otevírání dveří: -
 | Půdorys 1.NP | Zavěšené fasády | 1464Dve1096158508 | m2 | Stěna | NEW | 4.32 | 0.055 | 0.238 | 2.4 | 1.8 | NEMSOK - Object Layer Attributes #1, Směr otevírání dveří: -; Object Layer Attributes #1, Kód prvku: LP01.02.0002; Object Layer Attributes #1, 2D interakce: yes; Object Layer Attributes #1, Staticky nosná konstrukce: no; Object Layer Attributes #1, Materiál: PROSKLENÁ FASÁDA; Object Layer Attributes #1, Funkce (venkovní): Ano
Prostup stěnou | Půdorys 1.NP | Betonářské práce | 1464SVý1096316700 | m3 | Stěnový výklenek | NEW | 0.096 | 0.2 | 0.019 | 0.35 | 0.35 | NEMSOK - Object Layer Attributes #1, Označení: Prostup stěnou; Object Layer Attributes #1, Vnější průměr: 1010431516015xxxxxxx0
Prostup stěnou | Půdorys 1.NP | Betonářské práce | 1464SVý1096310594 | m3 | Stěnový výklenek | NEW | 0.125 | 0.3 | 0.038 | 0.25 | 0.5 | NEMSOK - Object Layer Attributes #1, Označení: Prostup stěnou
Okenní otvor | Půdorys 1.NP | Zateplovací systémy | 1464Okn1096167512 | m3 | Okenní otvor | NEW | 1.125 | 0.5 | 0.225 | 0.75 | 1.5 | NEMSOK - Object Layer Attributes #2, Status: Nový; Object Layer Attributes #2, Práce: Zateplovací systémy; Object Layer Attributes #2, Allright_Stavebni_dil_ID: 1464Okn1096167511; Object Layer Attributes #2, Jednotka: m3; Object Layer Attributes #2, Název_objektu: Okenní otvor; Object Layer Attributes #1, Označení: Okenní otvor; Object Layer Attributes #2, Označení: Okenní otvor
Dveřní otvor | Půdorys 1.NP | Betonářské práce | 1464Dve0000000321 | m3 | Dveřní otvor | NEW | 2.205 | 0.2 | 0.441 | 2.45 | 0.9 | NEMSOK - Object Layer Attributes #1, Směr otevírání dveří: L; Object Layer Attributes #1, Označení: Dveřní otvor
VZT | Půdorys 1.NP | Betonářské práce | 1464SVý1096310640 | m3 | Stěnový výklenek | NEW | 0.096 | 0.2 | 0.019 | 0.35 | 0.35 | NEMSOK - Object Layer Attributes #1, Označení: VZT
VZT | Půdorys 1.NP | Betonářské práce | 1464SVý1096310658 | m3 | Stěnový výklenek | NEW | 0.096 | 0.2 | 0.019 | 0.35 | 0.35 | NEMSOK - Object Layer Attributes #1, Označení: VZT
ZTI | Půdorys 1.NP | Betonářské práce | 1464SVý1096310706 | m3 | Stěnový výklenek | NEW | 0.031 | 0.2 | 0.006 | 0.2 | 0.2 | NEMSOK - Object Layer Attributes #1, Označení: ZTI
VZT | Půdorys 1.NP | Betonářské práce | 1464SVý1096310724 | m3 | Stěnový výklenek | NEW | 0.053 | 0.2 | 0.011 | 0.26 | 0.26 | NEMSOK - Object Layer Attributes #1, Označení: VZT
ZTI | Půdorys 1.NP | Suché stavební práce | 1464SVý1096310752 | m3 | Stěnový výklenek |  | 0.017 | 0.2 | 0.003 | 0.1 | 0.17 | NEMSOK - Object Layer Attributes #1, Označení: ZTI; Object Layer Attributes #1, Vnější průměr: 1010431516015xxxxxxx0
VZT+ZTI | Půdorys 1.NP | Suché stavební práce | 1464SVý1096310783 | m3 | Stěnový výklenek |  | 0.18 | 0.2 | 0.036 | 0.34 | 0.53 | NEMSOK - Object Layer Attributes #1, Označení: VZT+ZTI; Object Layer Attributes #1, Vnější průměr: 1010431516015xxxxxxx0
Dveřní otvor | Půdorys 1.NP | Betonářské práce | 1464Dve0000004735 | m3 | Dveřní otvor | NEW | 1.96 | 0.2 | 0.392 | 2.45 | 0.8 | NEMSOK - Object Layer Attributes #1, Směr otevírání dveří: P; Object Layer Attributes #1, Označení: Dveřní otvor
VZT | Půdorys 1.NP | Betonářské práce | 1464SVý1096311191 | m3 | Stěnový výklenek | NEW | 0.096 | 0.2 | 0.019 | 0.35 | 0.35 | NEMSOK - Object Layer Attributes #1, Označení: VZT
ZTI | Půdorys 1.NP | Suché stavební práce | 1464SVý1096311206 | m3 | Stěnový výklenek |  | 0.019 | 0.2 | 0.004 | 0.175 | 0.11 | NEMSOK - Object Layer Attributes #1, Označení: ZTI; Object Layer Attributes #1, Vnější průměr: 1010431516015xxxxxxx0
Dveřní otvor | Půdorys 1.NP | Betonářské práce | 1464Dve1096219257 | m3 | Dveřní otvor | NEW | 11.2 | 0.5 | 2.24 | 3.2 | 3.5 | NEMSOK - Object Layer Attributes #1, Směr otevírání dveří: -; Object Layer Attributes #2, Status: Nový; Object Layer Attributes #2, Práce: Betonářské práce; Object Layer Attributes #2, Allright_Stavebni_dil_ID: 1464Dve1096219256; Object Layer Attributes #2, Jednotka: m3; Object Layer Attributes #2, Název_objektu: Dveřní otvor; Object Layer Attributes #2, Směr otevírání dveří: -; Object Layer Attributes #1, Označení: Dveřní otvor; Object Layer Attributes #2, Označení: Dveřní otvor
Dveřní otvor | Půdorys 1.NP | Betonářské práce | 1464Dve0000001096 | m3 | Dveřní otvor | NEW | 2.45 | 0.2 | 0.49 | 2.45 | 1 | NEMSOK - Object Layer Attributes #1, Směr otevírání dveří: P; Object Layer Attributes #1, Označení: Dveřní otvor
Dveřní otvor | Půdorys 1.NP | Betonářské práce | 1464Dve1096123760 | m3 | Dveřní otvor | NEW | 2.45 | 0.2 | 0.49 | 2.45 | 1 | NEMSOK - Object Layer Attributes #1, Směr otevírání dveří: -; Object Layer Attributes #1, Označení: Dveřní otvor; Object Layer Attributes #1, Stupeň vyztužení: 3.05
ZTI | Půdorys 1.NP | Suché stavební práce | 1464SVý1096310845 | m3 | Stěnový výklenek |  | 0.03 | 0.2 | 0.006 | 0.11 | 0.275 | NEMSOK - Object Layer Attributes #1, Označení: ZTI; Object Layer Attributes #1, Vnější průměr: 1010431516015xxxxxxx0
VZT | Půdorys 1.NP | Suché stavební práce | 1464SVý1096311040 | m3 | Stěnový výklenek |  | 0.105 | 0.2 | 0.021 | 0.25 | 0.42 | NEMSOK - Object Layer Attributes #1, Označení: VZT; Object Layer Attributes #1, Vnější průměr: 1010431516015xxxxxxx0
ZTI | Půdorys 1.NP | Betonářské práce | 1464SVý1096311062 | m3 | Stěnový výklenek | NEW | 0.031 | 0.2 | 0.006 | 0.2 | 0.2 | NEMSOK - Object Layer Attributes #1, Označení: ZTI
VZT | Půdorys 1.NP | Betonářské práce | 1464SVý1096311751 | m3 | Stěnový výklenek | NEW | 0.071 | 0.2 | 0.014 | 0.3 | 0.3 | NEMSOK - Object Layer Attributes #1, Označení: VZT
Prostup stěnou | Půdorys 1.NP | Suché stavební práce | 1464SVý1096311838 | m3 | Stěnový výklenek |  | 0.008 | 0.04 | 0 | 0.04 | 0.19 | NEMSOK - Object Layer Attributes #1, Označení: Prostup stěnou; Object Layer Attributes #1, Vnější průměr: 1010431516015xxxxxxx0
Prostup stěnou | Půdorys 1.NP | Suché stavební práce | 1464SVý1096311849 | m3 | Stěnový výklenek |  | 0.098 | 0.04 | 0.004 | 2.44 | 0.04 | NEMSOK - Object Layer Attributes #1, Označení: Prostup stěnou; Object Layer Attributes #1, Vnější průměr: 1010431516015xxxxxxx0
Dveřní otvor | Půdorys 1.NP | Betonářské práce | 1464Dve1096158300 | m3 | Dveřní otvor | NEW | 3.6 | 0.2 | 0.72 | 2.4 | 1.5 | NEMSOK - Object Layer Attributes #1, Směr otevírání dveří: L; Object Layer Attributes #1, Označení: Dveřní otvor
VZT | Půdorys 1.NP | Suché stavební práce | 1464SVý1096309859 | m3 | Stěnový výklenek |  | 0.105 | 0.2 | 0.021 | 0.3 | 0.35 | NEMSOK - Object Layer Attributes #1, Označení: VZT; Object Layer Attributes #1, Vnější průměr: 1010431516015xxxxxxx0
VZT | Půdorys 1.NP | Suché stavební práce | 1464SVý1096309901 | m3 | Stěnový výklenek |  | 0.114 | 0.2 | 0.023 | 0.3 | 0.38 | NEMSOK - Object Layer Attributes #1, Označení: VZT; Object Layer Attributes #1, Vnější průměr: 1010431516015xxxxxxx0
Dveřní otvor | Půdorys 1.NP | Betonářské práce | 1464Dve1096158481 | m3 | Dveřní otvor | NEW | 3.36 | 0.2 | 0.672 | 2.4 | 1.4 | NEMSOK - Object Layer Attributes #1, Směr otevírání dveří: P; Object Layer Attributes #1, Označení: Dveřní otvor
VZT | Půdorys 1.NP | Suché stavební práce | 1464SVý1096309193 | m3 | Stěnový výklenek |  | 0.304 | 0.2 | 0.061 | 0.46 | 0.66 | NEMSOK - Object Layer Attributes #1, Označení: VZT; Object Layer Attributes #1, Vnější průměr: 1010431516015xxxxxxx0
VZT | Půdorys 1.NP | Suché stavební práce | 1464SVý1096309227 | m3 | Stěnový výklenek |  | 0.219 | 0.2 | 0.044 | 0.3 | 0.73 | NEMSOK - Object Layer Attributes #1, Označení: VZT; Object Layer Attributes #1, Vnější průměr: 1010431516015xxxxxxx0
VZT | Půdorys 1.NP | Suché stavební práce | 1464SVý1096309251 | m3 | Stěnový výklenek |  | 0.126 | 0.2 | 0.025 | 0.3 | 0.42 | NEMSOK - Object Layer Attributes #1, Označení: VZT; Object Layer Attributes #1, Vnější průměr: 1010431516015xxxxxxx0
Okenní otvor | Půdorys 1.NP | Zateplovací systémy | 1464Okn1096168434 | m3 | Okenní otvor | NEW | 1.125 | 0.55 | 0.281 | 0.75 | 1.5 | NEMSOK - Object Layer Attributes #2, Status: Nový; Object Layer Attributes #2, Práce: Zateplovací systémy; Object Layer Attributes #2, Allright_Stavebni_dil_ID: 1464Okn1096168433; Object Layer Attributes #2, Jednotka: m3; Object Layer Attributes #2, Název_objektu: Okenní otvor; Object Layer Attributes #1, Označení: Okenní otvor; Object Layer Attributes #2, Označení: Okenní otvor
Okenní otvor | Půdorys 1.NP | Zateplovací systémy | 1464Okn1096168502 | m3 | Okenní otvor | NEW | 1.125 | 0.55 | 0.281 | 0.75 | 1.5 | NEMSOK - Object Layer Attributes #2, Status: Nový; Object Layer Attributes #2, Práce: Zateplovací systémy; Object Layer Attributes #2, Allright_Stavebni_dil_ID: 1464Okn1096168503; Object Layer Attributes #2, Jednotka: m3; Object Layer Attributes #2, Název_objektu: Okenní otvor; Object Layer Attributes #1, Označení: Okenní otvor; Object Layer Attributes #2, Označení: Okenní otvor
Okenní otvor | Půdorys 1.NP | Zateplovací systémy | 1464Okn1096168546 | m3 | Okenní otvor | NEW | 1.125 | 0.55 | 0.281 | 0.75 | 1.5 | NEMSOK - Object Layer Attributes #2, Status: Nový; Object Layer Attributes #2, Práce: Zateplovací systémy; Object Layer Attributes #2, Allright_Stavebni_dil_ID: 1464Okn1096168544; Object Layer Attributes #2, Jednotka: m3; Object Layer Attributes #2, Název_objektu: Okenní otvor; Object Layer Attributes #1, Označení: Okenní otvor; Object Layer Attributes #2, Označení: Okenní otvor
Okenní otvor | Půdorys 1.NP | Zateplovací systémy | 1464Okn1096168608 | m3 | Okenní otvor | NEW | 1.125 | 0.55 | 0.281 | 0.75 | 1.5 | NEMSOK - Object Layer Attributes #2, Status: Nový; Object Layer Attributes #2, Práce: Zateplovací systémy; Object Layer Attributes #2, Allright_Stavebni_dil_ID: 1464Okn1096168607; Object Layer Attributes #2, Jednotka: m3; Object Layer Attributes #2, Název_objektu: Okenní otvor; Object Layer Attributes #1, Označení: Okenní otvor; Object Layer Attributes #2, Označení: Okenní otvor
Okenní otvor | Půdorys 1.NP | Zateplovací systémy | 1464Okn1096168642 | m3 | Okenní otvor | NEW | 1.125 | 0.55 | 0.281 | 0.75 | 1.5 | NEMSOK - Object Layer Attributes #2, Status: Nový; Object Layer Attributes #2, Práce: Zateplovací systémy; Object Layer Attributes #2, Allright_Stavebni_dil_ID: 1464Okn1096168643; Object Layer Attributes #2, Jednotka: m3; Object Layer Attributes #2, Název_objektu: Okenní otvor; Object Layer Attributes #1, Označení: Okenní otvor; Object Layer Attributes #2, Označení: Okenní otvor
Okenní otvor | Půdorys 1.NP | Zateplovací systémy | 1464Okn1096168674 | m3 | Okenní otvor | NEW | 1.125 | 0.55 | 0.281 | 0.75 | 1.5 | NEMSOK - Object Layer Attributes #2, Status: Nový; Object Layer Attributes #2, Práce: Zateplovací systémy; Object Layer Attributes #2, Allright_Stavebni_dil_ID: 1464Okn1096168673; Object Layer Attributes #2, Jednotka: m3; Object Layer Attributes #2, Název_objektu: Okenní otvor; Object Layer Attributes #1, Označení: Okenní otvor; Object Layer Attributes #2, Označení: Okenní otvor
Okenní otvor | Půdorys 1.NP | Zateplovací systémy | 1464Okn1096174662 | m3 | Okenní otvor | NEW | 1.125 | 0.55 | 0.281 | 0.75 | 1.5 | NEMSOK - Object Layer Attributes #2, Status: Nový; Object Layer Attributes #2, Práce: Zateplovací systémy; Object Layer Attributes #2, Allright_Stavebni_dil_ID: 1464Okn1096174661; Object Layer Attributes #2, Jednotka: m3; Object Layer Attributes #2, Název_objektu: Okenní otvor; Object Layer Attributes #1, Označení: Okenní otvor; Object Layer Attributes #2, Označení: Okenní otvor
VZT | Půdorys 1.NP | Betonářské práce | 1464SVý1096306566 | m3 | Stěnový výklenek | NEW | 0.071 | 0.2 | 0.014 | 0.3 | 0.3 | NEMSOK - Object Layer Attributes #1, Označení: VZT
VZT | Půdorys 1.NP | Betonářské práce | 1464SVý1096306587 | m3 | Stěnový výklenek | NEW | 0.071 | 0.2 | 0.014 | 0.3 | 0.3 | NEMSOK - Object Layer Attributes #1, Označení: VZT
Dveřní otvor | Půdorys 1.NP | Betonářské práce | 1464Dve1096159712 | m3 | Dveřní otvor | NEW | 11.59 | 0.55 | 2.897 | 3.05 | 3.8 | NEMSOK - Object Layer Attributes #1, Směr otevírání dveří: -; Object Layer Attributes #2, Status: Nový; Object Layer Attributes #2, Práce: Betonářské práce; Object Layer Attributes #2, Allright_Stavebni_dil_ID: 1464Dve1096159336; Object Layer Attributes #2, Jednotka: m3; Object Layer Attributes #2, Název_objektu: Dveřní otvor; Object Layer Attributes #2, Směr otevírání dveří: -; Object Layer Attributes #1, Označení: Dveřní otvor; Object Layer Attributes #2, Označení: Dveřní otvor
Okenní otvor | Půdorys 1.NP | Zateplovací systémy | 1464Okn1096167677 | m3 | Okenní otvor | NEW | 1.125 | 0.55 | 0.281 | 0.75 | 1.5 | NEMSOK - Object Layer Attributes #2, Status: Nový; Object Layer Attributes #2, Práce: Zateplovací systémy; Object Layer Attributes #2, Allright_Stavebni_dil_ID: 1464Okn1096167676; Object Layer Attributes #2, Jednotka: m3; Object Layer Attributes #2, Název_objektu: Okenní otvor; Object Layer Attributes #1, Označení: Okenní otvor; Object Layer Attributes #2, Označení: Okenní otvor
Stěnová nika | Půdorys 1.NP | Betonářské práce | 1464SNi1096215951 | m3 | Stěnová nika | NEW | 1.658 | 0.14 | 0.232 | 1.21 | 1.37 | NEMSOK - Object Layer Attributes #1, Označení: Stěnová nika
UT | Půdorys 1.NP | Betonářské práce | 1464SNi1096318362 | m3 | Stěnová nika | NEW | 0.025 | 0.11 | 0.003 | 0.25 | 0.1 | NEMSOK - Object Layer Attributes #1, Označení: UT
ZTI | Půdorys 1.NP | Betonářské práce | 1464SVý1096307167 | m3 | Stěnový výklenek | NEW | 0.008 | 0.43 | 0.003 | 0.1 | 0.1 | NEMSOK - Object Layer Attributes #1, Označení: ZTI
Stěnová nika | Půdorys 1.NP | Betonářské práce | 1464SNi1096205137 | m3 | Stěnová nika | NEW | 1.452 | 0.14 | 0.203 | 1.06 | 1.37 | NEMSOK - Object Layer Attributes #1, Označení: Stěnová nika
Dveřní otvor | Půdorys 1.NP | Betonářské práce | 1464Dve1096158009 | m3 | Dveřní otvor | NEW | 3.375 | 0.2 | 0.675 | 2.25 | 1.5 | NEMSOK - Object Layer Attributes #1, Směr otevírání dveří: -; Object Layer Attributes #1, Označení: Dveřní otvor
VZT | Půdorys 1.NP | Betonářské práce | 1464SVý1096309133 | m3 | Stěnový výklenek | NEW | 0.053 | 0.2 | 0.011 | 0.26 | 0.26 | NEMSOK - Object Layer Attributes #1, Označení: VZT
RAD | Půdorys 1.NP | Betonářské práce | 1464SNi1096318654 | m3 | Stěnová nika |  | 0.031 | 0.2 | 0.006 | 0.2 | 0.2 | NEMSOK - Object Layer Attributes #1, Označení: RAD; Object Layer Attributes #1, Vnější průměr: 15204125115375xxxxxx0
Okenní otvor | Půdorys 1.NP | Zateplovací systémy | 1464Okn1096168820 | m3 | Okenní otvor | NEW | 1.125 | 0.55 | 0.281 | 0.75 | 1.5 | NEMSOK - Object Layer Attributes #2, Status: Nový; Object Layer Attributes #2, Práce: Zateplovací systémy; Object Layer Attributes #2, Allright_Stavebni_dil_ID: 1464Okn1096168819; Object Layer Attributes #2, Jednotka: m3; Object Layer Attributes #2, Název_objektu: Okenní otvor; Object Layer Attributes #1, Označení: Okenní otvor; Object Layer Attributes #2, Označení: Okenní otvor
Okenní otvor | Půdorys 1.NP | Zateplovací systémy | 1464Okn1096168851 | m3 | Okenní otvor | NEW | 1.125 | 0.55 | 0.281 | 0.75 | 1.5 | NEMSOK - Object Layer Attributes #2, Status: Nový; Object Layer Attributes #2, Práce: Zateplovací systémy; Object Layer Attributes #2, Allright_Stavebni_dil_ID: 1464Okn1096168852; Object Layer Attributes #2, Jednotka: m3; Object Layer Attributes #2, Název_objektu: Okenní otvor; Object Layer Attributes #1, Označení: Okenní otvor; Object Layer Attributes #2, Označení: Okenní otvor
Okenní otvor | Půdorys 1.NP | Zateplovací systémy | 1464Okn1096168895 | m3 | Okenní otvor | NEW | 1.125 | 0.55 | 0.281 | 0.75 | 1.5 | NEMSOK - Object Layer Attributes #2, Status: Nový; Object Layer Attributes #2, Práce: Zateplovací systémy; Object Layer Attributes #2, Allright_Stavebni_dil_ID: 1464Okn1096168894; Object Layer Attributes #2, Jednotka: m3; Object Layer Attributes #2, Název_objektu: Okenní otvor; Object Layer Attributes #1, Označení: Okenní otvor; Object Layer Attributes #2, Označení: Okenní otvor
Okenní otvor | Půdorys 1.NP | Zateplovací systémy | 1464Okn1096168925 | m3 | Okenní otvor | NEW | 1.125 | 0.55 | 0.281 | 0.75 | 1.5 | NEMSOK - Object Layer Attributes #2, Status: Nový; Object Layer Attributes #2, Práce: Zateplovací systémy; Object Layer Attributes #2, Allright_Stavebni_dil_ID: 1464Okn1096168926; Object Layer Attributes #2, Jednotka: m3; Object Layer Attributes #2, Název_objektu: Okenní otvor; Object Layer Attributes #1, Označení: Okenní otvor; Object Layer Attributes #2, Označení: Okenní otvor
Dveřní otvor | Půdorys 1.NP | Betonářské práce | 1464Dve1096159624 | m3 | Dveřní otvor | NEW | 2.45 | 0.2 | 0.49 | 2.45 | 1 | NEMSOK - Object Layer Attributes #1, Směr otevírání dveří: L; Object Layer Attributes #1, Označení: Dveřní otvor
Dveřní otvor | Půdorys 1.NP | Betonářské práce | 1464Dve1096159629 | m3 | Dveřní otvor | NEW | 2.45 | 0.2 | 0.49 | 2.45 | 1 | NEMSOK - Object Layer Attributes #1, Směr otevírání dveří: L; Object Layer Attributes #1, Označení: Dveřní otvor
Dveřní otvor | Půdorys 1.NP | Betonářské práce | 1464Dve1096159633 | m3 | Dveřní otvor | NEW | 2.45 | 0.2 | 0.49 | 2.45 | 1 | NEMSOK - Object Layer Attributes #1, Směr otevírání dveří: P; Object Layer Attributes #1, Označení: Dveřní otvor
ZTI | Půdorys 1.NP | Suché stavební práce | 1464SVý1096306827 | m3 | Stěnový výklenek |  | 0.019 | 0.2 | 0.004 | 0.11 | 0.175 | NEMSOK - Object Layer Attributes #1, Označení: ZTI; Object Layer Attributes #1, Vnější průměr: 1010431516015xxxxxxx0
UT | Půdorys 1.NP | Betonářské práce | 1464SNi1096318354 | m3 | Stěnová nika | NEW | 0.025 | 0.23 | 0.006 | 0.25 | 0.1 | NEMSOK - Object Layer Attributes #1, Označení: UT
Prostup stěnou | Půdorys 1.NP | Suché stavební práce | 1464SVý1096316567 | m3 | Stěnový výklenek |  | 0.1 | 0.22 | 0.022 | 0.1 | 1 | NEMSOK - Object Layer Attributes #1, Označení: Prostup stěnou; Object Layer Attributes #1, Vnější průměr: 1010431516015xxxxxxx0
Prostup stěnou | Půdorys 1.NP | Suché stavební práce | 1464SVý1096316423 | m3 | Stěnový výklenek |  | 0.1 | 0.22 | 0.022 | 0.1 | 1 | NEMSOK - Object Layer Attributes #1, Označení: Prostup stěnou; Object Layer Attributes #1, Vnější průměr: 1010431516015xxxxxxx0
Okenní otvor | Půdorys 1.NP | Zateplovací systémy | 1464Okn1096168111 | m3 | Okenní otvor | NEW | 1.125 | 0.55 | 0.281 | 0.75 | 1.5 | NEMSOK - Object Layer Attributes #2, Status: Nový; Object Layer Attributes #2, Práce: Zateplovací systémy; Object Layer Attributes #2, Allright_Stavebni_dil_ID: 1464Okn1096168110; Object Layer Attributes #2, Jednotka: m3; Object Layer Attributes #2, Název_objektu: Okenní otvor; Object Layer Attributes #1, Označení: Okenní otvor; Object Layer Attributes #2, Označení: Okenní otvor
Okenní otvor | Půdorys 1.NP | Zateplovací systémy | 1464Okn1096168142 | m3 | Okenní otvor | NEW | 1.125 | 0.55 | 0.281 | 0.75 | 1.5 | NEMSOK - Object Layer Attributes #2, Status: Nový; Object Layer Attributes #2, Práce: Zateplovací systémy; Object Layer Attributes #2, Allright_Stavebni_dil_ID: 1464Okn1096168141; Object Layer Attributes #2, Jednotka: m3; Object Layer Attributes #2, Název_objektu: Okenní otvor; Object Layer Attributes #1, Označení: Okenní otvor; Object Layer Attributes #2, Označení: Okenní otvor
ZTI | Půdorys 1.NP | Betonářské práce | 1464SVý1096308307 | m3 | Stěnový výklenek | NEW | 0.019 | 0.3 | 0.006 | 0.175 | 0.11 | NEMSOK - Object Layer Attributes #1, Označení: ZTI
Dveřní otvor | Půdorys 1.NP | Betonářské práce | 1464Dve1096159486 | m3 | Dveřní otvor | NEW | 3.3 | 0.3 | 0.99 | 2.2 | 1.5 | NEMSOK - Object Layer Attributes #1, Směr otevírání dveří: L; Object Layer Attributes #1, Označení: Dveřní otvor
Dveřní otvor | Půdorys 1.NP | Betonářské práce | 1464Dve1096213712 | m3 | Dveřní otvor | NEW | 2.75 | 0.25 | 0.687 | 2.2 | 1.25 | NEMSOK - Object Layer Attributes #1, Směr otevírání dveří: -; Object Layer Attributes #1, Označení: Dveřní otvor
Dveřní otvor | Půdorys 1.NP | Betonářské práce | 1464Dve1096214221 | m3 | Dveřní otvor | NEW | 3.3 | 0.25 | 0.825 | 2.2 | 1.5 | NEMSOK - Object Layer Attributes #1, Směr otevírání dveří: P; Object Layer Attributes #1, Označení: Dveřní otvor
Dveřní otvor | Půdorys 1.NP | Betonářské práce | 1464Dve1096214667 | m3 | Dveřní otvor | NEW | 2.75 | 0.25 | 0.687 | 2.2 | 1.25 | NEMSOK - Object Layer Attributes #1, Směr otevírání dveří: -; Object Layer Attributes #1, Označení: Dveřní otvor
Dveřní otvor | Půdorys 1.NP | Betonářské práce | 1464Dve1096214885 | m3 | Dveřní otvor | NEW | 2.75 | 0.25 | 0.687 | 2.2 | 1.25 | NEMSOK - Object Layer Attributes #1, Směr otevírání dveří: -; Object Layer Attributes #1, Označení: Dveřní otvor
ELE | Půdorys 1.NP | Betonářské práce | 1464SNi1096318528 | m3 | Stěnová nika | NEW | 0.098 | 0.25 | 0.024 | 0.15 | 0.65 | NEMSOK - Object Layer Attributes #1, Označení: ELE
ELE | Půdorys 1.NP | Betonářské práce | 1464SNi1096318575 | m3 | Stěnová nika | NEW | 0.053 | 0.25 | 0.013 | 0.15 | 0.35 | NEMSOK - Object Layer Attributes #1, Označení: ELE
VZT | Půdorys 1.NP | Suché stavební práce | 1464SVý1096309069 | m3 | Stěnový výklenek |  | 0.165 | 0.25 | 0.041 | 0.3 | 0.55 | NEMSOK - Object Layer Attributes #1, Označení: VZT; Object Layer Attributes #1, Vnější průměr: 1010431516015xxxxxxx0
VZT | Půdorys 1.NP | Suché stavební práce | 1464SVý1096309278 | m3 | Stěnový výklenek |  | 0.18 | 0.25 | 0.045 | 0.3 | 0.6 | NEMSOK - Object Layer Attributes #1, Označení: VZT; Object Layer Attributes #1, Vnější průměr: 1010431516015xxxxxxx0
Dveřní otvor | Půdorys 1.NP | Betonářské práce | 1464Dve1096215243 | m3 | Dveřní otvor | NEW | 2.75 | 0.3 | 0.825 | 2.2 | 1.25 | NEMSOK - Object Layer Attributes #1, Směr otevírání dveří: -; Object Layer Attributes #1, Označení: Dveřní otvor
ELE | Půdorys 1.NP | Suché stavební práce | 1464SNi1096318601 | m3 | Stěnová nika |  | 0.052 | 0.3 | 0.016 | 0.15 | 0.35 | NEMSOK - Object Layer Attributes #1, Označení: ELE; Object Layer Attributes #1, Vnější průměr: 1010431516015xxxxxxx0
VZT | Půdorys 1.NP | Betonářské práce | 1464SVý1096309547 | m3 | Stěnový výklenek | NEW | 0.04 | 0.3 | 0.012 | 0.225 | 0.225 | NEMSOK - Object Layer Attributes #1, Označení: VZT
Dveřní otvor | Půdorys 1.NP | Betonářské práce | 1464Dve1096161094 | m3 | Dveřní otvor | NEW | 1.696 | 0.125 | 0.212 | 2.12 | 0.8 | NEMSOK - Object Layer Attributes #1, Směr otevírání dveří: P; Object Layer Attributes #1, Označení: Dveřní otvor; Object Layer Attributes #1, Podlaží: 1.NP
Dveřní otvor | Půdorys 1.NP | Betonářské práce | 1464Dve1096216497 | m3 | Dveřní otvor | NEW | 2.12 | 0.125 | 0.265 | 2.12 | 1 | NEMSOK - Object Layer Attributes #1, Směr otevírání dveří: L; Object Layer Attributes #1, Označení: Dveřní otvor; Object Layer Attributes #1, Podlaží: 1.NP
Dveřní otvor | Půdorys 1.NP | Betonářské práce | 1464Dve1096164071 | m3 | Dveřní otvor | NEW | 2.875 | 0.125 | 0.359 | 2.3 | 1.25 | NEMSOK - Object Layer Attributes #1, Směr otevírání dveří: -; Object Layer Attributes #1, Označení: Dveřní otvor; Object Layer Attributes #1, Podlaží: 1.NP
Dveřní otvor | Půdorys 1.NP | Betonářské práce | 1464Dve1096157579 | m3 | Dveřní otvor | NEW | 3.286 | 0.125 | 0.411 | 2.12 | 1.55 | NEMSOK - Object Layer Attributes #1, Směr otevírání dveří: -; Object Layer Attributes #1, Označení: Dveřní otvor; Object Layer Attributes #1, Podlaží: 1.NP
Dveřní otvor | Půdorys 1.NP | Betonářské práce | 1464Dve1096163806 | m3 | Dveřní otvor | NEW | 1.908 | 0.125 | 0.238 | 2.12 | 0.9 | NEMSOK - Object Layer Attributes #1, Směr otevírání dveří: L; Object Layer Attributes #1, Označení: Dveřní otvor; Object Layer Attributes #1, Podlaží: 1.NP
Dveřní otvor | Půdorys 1.NP | Betonářské práce | 1464Dve1096288783 | m3 | Dveřní otvor | NEW | 2.12 | 0.125 | 0.265 | 2.12 | 1 | NEMSOK - Object Layer Attributes #1, Směr otevírání dveří: L; Object Layer Attributes #1, Označení: Dveřní otvor; Object Layer Attributes #1, Podlaží: 1.NP
Dveřní otvor | Půdorys 1.NP | Betonářské práce | 1464Dve1096144128 | m3 | Dveřní otvor | EXISTING | 0.731 | 0.032 | 0.023 | 0.85 | 0.86 | NEMSOK - Object Layer Attributes #1, Směr otevírání dveří: P; Object Layer Attributes #1, Označení: Dveřní otvor
Dveřní otvor | Půdorys 1.NP | Zavěšené fasády | 1464Dve1096158503 | m3 | Dveřní otvor | NEW | 3.78 | 0.055 | 0.208 | 2.1 | 1.8 | NEMSOK - Object Layer Attributes #1, Směr otevírání dveří: -; Object Layer Attributes #1, Označení: Dveřní otvor
ZTI HL. 40 | Půdorys 1.NP | Suché stavební práce | 1464SVý1096309944 | m3 | Stěnový výklenek |  | 0.116 | 0.04 | 0.005 | 2.89 | 0.04 | NEMSOK - Object Layer Attributes #1, Označení: ZTI HL. 40; Object Layer Attributes #1, Vnější průměr: 1010431516015xxxxxxx0
VZT | Půdorys 1.NP | Betonářské práce | 1464SVý1096309929 | m3 | Stěnový výklenek | NEW | 0.04 | 0.1 | 0.004 | 0.225 | 0.225 | NEMSOK - Object Layer Attributes #1, Označení: VZT
VZT | Půdorys 1.NP | Suché stavební práce | 1464SVý1096308844 | m3 | Stěnový výklenek |  | 0.15 | 0.1 | 0.015 | 0.3 | 0.5 | NEMSOK - Object Layer Attributes #1, Označení: VZT; Object Layer Attributes #1, Vnější průměr: 1010431516015xxxxxxx0
ZTI | Půdorys 1.NP | Betonářské práce | 1464SVý1096308867 | m3 | Stěnový výklenek | NEW | 0.031 | 0.1 | 0.003 | 0.2 | 0.2 | NEMSOK - Object Layer Attributes #1, Označení: ZTI
VZT | Půdorys 1.NP | Suché stavební práce | 1464SVý1096308830 | m3 | Stěnový výklenek |  | 0.114 | 0.1 | 0.011 | 0.3 | 0.38 | NEMSOK - Object Layer Attributes #1, Označení: VZT; Object Layer Attributes #1, Vnější průměr: 1010431516015xxxxxxx0
VZT | Půdorys 1.NP | Betonářské práce | 1464SVý1096308020 | m3 | Stěnový výklenek | NEW | 0.04 | 0.1 | 0.004 | 0.225 | 0.225 | NEMSOK - Object Layer Attributes #1, Označení: VZT
VZT | Půdorys 1.NP | Betonářské práce | 1464SVý1096308046 | m3 | Stěnový výklenek | NEW | 0.04 | 0.1 | 0.004 | 0.225 | 0.225 | NEMSOK - Object Layer Attributes #1, Označení: VZT
VZT | Půdorys 1.NP | Betonářské práce | 1464SVý1096308062 | m3 | Stěnový výklenek | NEW | 0.04 | 0.1 | 0.004 | 0.225 | 0.225 | NEMSOK - Object Layer Attributes #1, Označení: VZT
VZT | Půdorys 1.NP | Betonářské práce | 1464SVý1096308780 | m3 | Stěnový výklenek | NEW | 0.04 | 0.1 | 0.004 | 0.225 | 0.225 | NEMSOK - Object Layer Attributes #1, Označení: VZT
VZT | Půdorys 1.NP | Betonářské práce | 1464SVý1096308794 | m3 | Stěnový výklenek | NEW | 0.04 | 0.1 | 0.004 | 0.225 | 0.225 | NEMSOK - Object Layer Attributes #1, Označení: VZT
VZT | Půdorys 1.NP | Suché stavební práce | 1464SVý1096306757 | m3 | Stěnový výklenek |  | 0.093 | 0.1 | 0.009 | 0.3 | 0.31 | NEMSOK - Object Layer Attributes #1, Označení: VZT; Object Layer Attributes #1, Vnější průměr: 1010431516015xxxxxxx0
VZT | Půdorys 1.NP | Suché stavební práce | 1464SVý1096307968 | m3 | Stěnový výklenek |  | 0.093 | 0.1 | 0.009 | 0.3 | 0.31 | NEMSOK - Object Layer Attributes #1, Označení: VZT; Object Layer Attributes #1, Vnější průměr: 1010431516015xxxxxxx0
VZT | Půdorys 1.NP | Suché stavební práce | 1464SVý1096307985 | m3 | Stěnový výklenek |  | 0.105 | 0.1 | 0.011 | 0.3 | 0.35 | NEMSOK - Object Layer Attributes #1, Označení: VZT; Object Layer Attributes #1, Vnější průměr: 1010431516015xxxxxxx0
VZT | Půdorys 1.NP | Suché stavební práce | 1464SVý1096308007 | m3 | Stěnový výklenek |  | 0.105 | 0.1 | 0.01 | 0.3 | 0.35 | NEMSOK - Object Layer Attributes #1, Označení: VZT; Object Layer Attributes #1, Vnější průměr: 1010431516015xxxxxxx0
VZT | Půdorys 1.NP | Suché stavební práce | 1464SVý1096308811 | m3 | Stěnový výklenek |  | 0.114 | 0.1 | 0.011 | 0.3 | 0.38 | NEMSOK - Object Layer Attributes #1, Označení: VZT; Object Layer Attributes #1, Vnější průměr: 1010431516015xxxxxxx0
VZT | Půdorys 1.NP | Suché stavební práce | 1464SVý1096306679 | m3 | Stěnový výklenek |  | 0.168 | 0.1 | 0.017 | 0.3 | 0.56 | NEMSOK - Object Layer Attributes #1, Označení: VZT; Object Layer Attributes #1, Vnější průměr: 1010431516015xxxxxxx0
Dveřní otvor | Půdorys 1.NP | Suché stavební práce | 1464Dve1096312757 | m3 | Stěna | NEW | 3.96 | 0.125 | 0.495 | 2.2 | 1.8 | NEMSOK - Object Layer Attributes #1, Směr otevírání dveří: -; Object Layer Attributes #1, Označení: Dveřní otvor; Object Layer Attributes #1, Kód prvku: SN07.03.0001; Object Layer Attributes #1, Podlaží: 1.NP; Object Layer Attributes #1, 2D interakce: yes; Object Layer Attributes #1, Staticky nosná konstrukce: no; Object Layer Attributes #1, Požární odolnost: EI 60; Object Layer Attributes #1, Statická funkce: Ne; Object Layer Attributes #1, Funkce (venkovní): Ne; Object Layer Attributes #1, Vážená stavební neprůzvučnost: 54; Object Layer Attributes #1, Vlhkostní namáhání oboustranné: Ne; Object Layer Attributes #1, Tloušťka opláštění: 2×12,5; Object Layer Attributes #1, Typ SDK desky: vysokopevnostní+bílá; Object Layer Attributes #1, Způsob opláštění: Oboustranné; Object Layer Attributes #1, Tloušťka izolace (2): 100; Object Layer Attributes #1, Objemová hmotnost izolace: 25; Object Layer Attributes #1, Typ profilu pro SDK: CW 100
ZTI | Půdorys 1.NP | Suché stavební práce | 1464SVý1096314577 | m3 | Stěna | NEW | 0.05 | 0.125 | 0.006 | 0.15 | 0.33 | NEMSOK - Object Layer Attributes #1, Označení: ZTI; Object Layer Attributes #1, Kód prvku: SN07.03.0001; Object Layer Attributes #1, Podlaží: 1.NP; Object Layer Attributes #1, 2D interakce: yes; Object Layer Attributes #1, Staticky nosná konstrukce: no; Object Layer Attributes #1, Požární odolnost: EI 60; Object Layer Attributes #1, Statická funkce: Ne; Object Layer Attributes #1, Vnější průměr: 1010431516015xxxxxxx0; Object Layer Attributes #1, Funkce (venkovní): Ne; Object Layer Attributes #1, Vážená stavební neprůzvučnost: 54; Object Layer Attributes #1, Vlhkostní namáhání oboustranné: Ne; Object Layer Attributes #1, Tloušťka opláštění: 2×12,5; Object Layer Attributes #1, Typ SDK desky: vysokopevnostní+bílá; Object Layer Attributes #1, Způsob opláštění: Oboustranné; Object Layer Attributes #1, Tloušťka izolace (2): 100; Object Layer Attributes #1, Objemová hmotnost izolace: 25; Object Layer Attributes #1, Typ profilu pro SDK: CW 100
Stěnová nika | Půdorys 1.NP | Suché stavební práce | 1464SNi1096313509 | m3 | Stěna | NEW | 0.04 | 0.05 | 0.002 | 0.2 | 0.2 | NEMSOK - Object Layer Attributes #1, Označení: Stěnová nika; Object Layer Attributes #1, Kód prvku: SN07.03.0001; Object Layer Attributes #1, Podlaží: 1.NP; Object Layer Attributes #1, 2D interakce: yes; Object Layer Attributes #1, Staticky nosná konstrukce: no; Object Layer Attributes #1, Požární odolnost: EI 60; Object Layer Attributes #1, Statická funkce: Ne; Object Layer Attributes #1, Funkce (venkovní): Ne; Object Layer Attributes #1, Vážená stavební neprůzvučnost: 54; Object Layer Attributes #1, Vlhkostní namáhání oboustranné: Ne; Object Layer Attributes #1, Tloušťka opláštění: 2×12,5; Object Layer Attributes #1, Typ SDK desky: vysokopevnostní+bílá; Object Layer Attributes #1, Způsob opláštění: Oboustranné; Object Layer Attributes #1, Tloušťka izolace (2): 100; Object Layer Attributes #1, Objemová hmotnost izolace: 25; Object Layer Attributes #1, Typ profilu pro SDK: CW 100
Dveřní otvor | Půdorys 1.NP | Suché stavební práce | 1464Dve1096314624 | m3 | Stěna | NEW | 1.8 | 0.1 | 0.18 | 2.25 | 0.8 | NEMSOK - Object Layer Attributes #1, Směr otevírání dveří: L; Object Layer Attributes #1, Označení: Dveřní otvor; Object Layer Attributes #1, Kód prvku: SN07.03.0001; Object Layer Attributes #1, Podlaží: 1.NP; Object Layer Attributes #1, 2D interakce: yes; Object Layer Attributes #1, Staticky nosná konstrukce: no; Object Layer Attributes #1, Požární odolnost: EI 60; Object Layer Attributes #1, Statická funkce: Ne; Object Layer Attributes #1, Funkce (venkovní): Ne; Object Layer Attributes #1, Vážená stavební neprůzvučnost: 54; Object Layer Attributes #1, Vlhkostní namáhání oboustranné: Ne; Object Layer Attributes #1, Tloušťka opláštění: 2×12,5; Object Layer Attributes #1, Typ SDK desky: vysokopevnostní+bílá; Object Layer Attributes #1, Způsob opláštění: Oboustranné; Object Layer Attributes #1, Tloušťka izolace (2): 100; Object Layer Attributes #1, Objemová hmotnost izolace: 25; Object Layer Attributes #1, Typ profilu pro SDK: CW 100
VZT | Půdorys 1.NP | Suché stavební práce | 1464SVý1096314544 | m3 | Stěna | NEW | 0.049 | 0.1 | 0.005 | 0.25 | 0.25 | NEMSOK - Object Layer Attributes #1, Označení: VZT; Object Layer Attributes #1, Kód prvku: SN07.03.0001; Object Layer Attributes #1, Podlaží: 1.NP; Object Layer Attributes #1, 2D interakce: yes; Object Layer Attributes #1, Staticky nosná konstrukce: no; Object Layer Attributes #1, Požární odolnost: EI 60; Object Layer Attributes #1, Statická funkce: Ne; Object Layer Attributes #1, Funkce (venkovní): Ne; Object Layer Attributes #1, Vážená stavební neprůzvučnost: 54; Object Layer Attributes #1, Vlhkostní namáhání oboustranné: Ne; Object Layer Attributes #1, Tloušťka opláštění: 2×12,5; Object Layer Attributes #1, Typ SDK desky: vysokopevnostní+bílá; Object Layer Attributes #1, Způsob opláštění: Oboustranné; Object Layer Attributes #1, Tloušťka izolace (2): 100; Object Layer Attributes #1, Objemová hmotnost izolace: 25; Object Layer Attributes #1, Typ profilu pro SDK: CW 100
ZTI | Půdorys 1.NP | Suché stavební práce | 1464SVý1096314621 | m3 | Stěna | NEW | 0.031 | 0.1 | 0.003 | 0.2 | 0.2 | NEMSOK - Object Layer Attributes #1, Označení: ZTI; Object Layer Attributes #1, Kód prvku: SN07.03.0001; Object Layer Attributes #1, Podlaží: 1.NP; Object Layer Attributes #1, 2D interakce: yes; Object Layer Attributes #1, Staticky nosná konstrukce: no; Object Layer Attributes #1, Požární odolnost: EI 60; Object Layer Attributes #1, Statická funkce: Ne; Object Layer Attributes #1, Funkce (venkovní): Ne; Object Layer Attributes #1, Vážená stavební neprůzvučnost: 54; Object Layer Attributes #1, Vlhkostní namáhání oboustranné: Ne; Object Layer Attributes #1, Tloušťka opláštění: 2×12,5; Object Layer Attributes #1, Typ SDK desky: vysokopevnostní+bílá; Object Layer Attributes #1, Způsob opláštění: Oboustranné; Object Layer Attributes #1, Tloušťka izolace (2): 100; Object Layer Attributes #1, Objemová hmotnost izolace: 25; Object Layer Attributes #1, Typ profilu pro SDK: CW 100
Dveřní otvor | Půdorys 1.NP | Suché stavební práce | 1464Dve1096314511 | m3 | Stěna | NEW | 2.025 | 0.125 | 0.253 | 2.25 | 0.9 | NEMSOK - Object Layer Attributes #1, Směr otevírání dveří: P; Object Layer Attributes #1, Označení: Dveřní otvor; Object Layer Attributes #1, Kód prvku: SN07.03.0001; Object Layer Attributes #1, Podlaží: 1.NP; Object Layer Attributes #1, 2D interakce: yes; Object Layer Attributes #1, Staticky nosná konstrukce: no; Object Layer Attributes #1, Požární odolnost: EI 60; Object Layer Attributes #1, Statická funkce: Ne; Object Layer Attributes #1, Funkce (venkovní): Ne; Object Layer Attributes #1, Vážená stavební neprůzvučnost: 54; Object Layer Attributes #1, Vlhkostní namáhání oboustranné: Ne; Object Layer Attributes #1, Tloušťka opláštění: 2×12,5; Object Layer Attributes #1, Typ SDK desky: vysokopevnostní+bílá; Object Layer Attributes #1, Způsob opláštění: Oboustranné; Object Layer Attributes #1, Tloušťka izolace (2): 100; Object Layer Attributes #1, Objemová hmotnost izolace: 25; Object Layer Attributes #1, Typ profilu pro SDK: CW 100
Dveřní otvor | Půdorys 1.NP | Suché stavební práce | 1464Dve1096314655 | m3 | Stěna | NEW | 2.025 | 0.125 | 0.253 | 2.25 | 0.9 | NEMSOK - Object Layer Attributes #1, Směr otevírání dveří: L; Object Layer Attributes #1, Označení: Dveřní otvor; Object Layer Attributes #1, Kód prvku: SN07.03.0001; Object Layer Attributes #1, Podlaží: 1.NP; Object Layer Attributes #1, 2D interakce: yes; Object Layer Attributes #1, Staticky nosná konstrukce: no; Object Layer Attributes #1, Požární odolnost: EI 60; Object Layer Attributes #1, Statická funkce: Ne; Object Layer Attributes #1, Funkce (venkovní): Ne; Object Layer Attributes #1, Vážená stavební neprůzvučnost: 54; Object Layer Attributes #1, Vlhkostní namáhání oboustranné: Ne; Object Layer Attributes #1, Tloušťka opláštění: 2×12,5; Object Layer Attributes #1, Typ SDK desky: vysokopevnostní+bílá; Object Layer Attributes #1, Způsob opláštění: Oboustranné; Object Layer Attributes #1, Tloušťka izolace (2): 100; Object Layer Attributes #1, Objemová hmotnost izolace: 25; Object Layer Attributes #1, Typ profilu pro SDK: CW 100
ZTI | Půdorys 1.NP | Suché stavební práce | 1464SVý1096314521 | m3 | Stěna | NEW | 0.019 | 0.125 | 0.002 | 0.11 | 0.175 | NEMSOK - Object Layer Attributes #1, Označení: ZTI; Object Layer Attributes #1, Kód prvku: SN07.03.0001; Object Layer Attributes #1, Podlaží: 1.NP; Object Layer Attributes #1, 2D interakce: yes; Object Layer Attributes #1, Staticky nosná konstrukce: no; Object Layer Attributes #1, Požární odolnost: EI 60; Object Layer Attributes #1, Statická funkce: Ne; Object Layer Attributes #1, Vnější průměr: 1010431516015xxxxxxx0; Object Layer Attributes #1, Funkce (venkovní): Ne; Object Layer Attributes #1, Vážená stavební neprůzvučnost: 54; Object Layer Attributes #1, Vlhkostní namáhání oboustranné: Ne; Object Layer Attributes #1, Tloušťka opláštění: 2×12,5; Object Layer Attributes #1, Typ SDK desky: vysokopevnostní+bílá; Object Layer Attributes #1, Způsob opláštění: Oboustranné; Object Layer Attributes #1, Tloušťka izolace (2): 100; Object Layer Attributes #1, Objemová hmotnost izolace: 25; Object Layer Attributes #1, Typ profilu pro SDK: CW 100
VZT+ZTI | Půdorys 1.NP | Suché stavební práce | 1464SVý1096314673 | m3 | Stěna | NEW | 0.116 | 0.125 | 0.014 | 0.29 | 0.4 | NEMSOK - Object Layer Attributes #1, Označení: VZT+ZTI; Object Layer Attributes #1, Kód prvku: SN07.03.0001; Object Layer Attributes #1, Podlaží: 1.NP; Object Layer Attributes #1, 2D interakce: yes; Object Layer Attributes #1, Staticky nosná konstrukce: no; Object Layer Attributes #1, Požární odolnost: EI 60; Object Layer Attributes #1, Statická funkce: Ne; Object Layer Attributes #1, Funkce (venkovní): Ne; Object Layer Attributes #1, Vážená stavební neprůzvučnost: 54; Object Layer Attributes #1, Vlhkostní namáhání oboustranné: Ne; Object Layer Attributes #1, Tloušťka opláštění: 2×12,5; Object Layer Attributes #1, Typ SDK desky: vysokopevnostní+bílá; Object Layer Attributes #1, Způsob opláštění: Oboustranné; Object Layer Attributes #1, Tloušťka izolace (2): 100; Object Layer Attributes #1, Objemová hmotnost izolace: 25; Object Layer Attributes #1, Typ profilu pro SDK: CW 100
Dveřní otvor | Půdorys 1.NP | Suché stavební práce | 1464Dve1096312762 | m3 | Stěna | NEW | 2.025 | 0.125 | 0.253 | 2.25 | 0.9 | NEMSOK - Object Layer Attributes #1, Směr otevírání dveří: L; Object Layer Attributes #1, Označení: Dveřní otvor; Object Layer Attributes #1, Kód prvku: SN07.03.0001; Object Layer Attributes #1, Podlaží: 1.NP; Object Layer Attributes #1, 2D interakce: yes; Object Layer Attributes #1, Staticky nosná konstrukce: no; Object Layer Attributes #1, Požární odolnost: EI 60; Object Layer Attributes #1, Statická funkce: Ne; Object Layer Attributes #1, Funkce (venkovní): Ne; Object Layer Attributes #1, Vážená stavební neprůzvučnost: 54; Object Layer Attributes #1, Vlhkostní namáhání oboustranné: Ne; Object Layer Attributes #1, Tloušťka opláštění: 2×12,5; Object Layer Attributes #1, Typ SDK desky: vysokopevnostní+bílá; Object Layer Attributes #1, Způsob opláštění: Oboustranné; Object Layer Attributes #1, Tloušťka izolace (2): 100; Object Layer Attributes #1, Objemová hmotnost izolace: 25; Object Layer Attributes #1, Typ profilu pro SDK: CW 100
Stěnová nika | Půdorys 1.NP | Suché stavební práce | 1464SNi1096313517 | m3 | Stěna | NEW | 0.04 | 0.05 | 0.002 | 0.2 | 0.2 | NEMSOK - Object Layer Attributes #1, Označení: Stěnová nika; Object Layer Attributes #1, Kód prvku: SN07.03.0001; Object Layer Attributes #1, Podlaží: 1.NP; Object Layer Attributes #1, 2D interakce: yes; Object Layer Attributes #1, Staticky nosná konstrukce: no; Object Layer Attributes #1, Požární odolnost: EI 60; Object Layer Attributes #1, Statická funkce: Ne; Object Layer Attributes #1, Funkce (venkovní): Ne; Object Layer Attributes #1, Vážená stavební neprůzvučnost: 54; Object Layer Attributes #1, Vlhkostní namáhání oboustranné: Ne; Object Layer Attributes #1, Tloušťka opláštění: 2×12,5; Object Layer Attributes #1, Typ SDK desky: vysokopevnostní+bílá; Object Layer Attributes #1, Způsob opláštění: Oboustranné; Object Layer Attributes #1, Tloušťka izolace (2): 100; Object Layer Attributes #1, Objemová hmotnost izolace: 25; Object Layer Attributes #1, Typ profilu pro SDK: CW 100
VZT | Půdorys 1.NP | Suché stavební práce | 1464SVý1096314193 | m3 | Stěna | NEW | 0.031 | 0.125 | 0.004 | 0.2 | 0.2 | NEMSOK - Object Layer Attributes #1, Označení: VZT; Object Layer Attributes #1, Kód prvku: SN07.03.0001; Object Layer Attributes #1, Podlaží: 1.NP; Object Layer Attributes #1, 2D interakce: yes; Object Layer Attributes #1, Staticky nosná konstrukce: no; Object Layer Attributes #1, Požární odolnost: EI 60; Object Layer Attributes #1, Statická funkce: Ne; Object Layer Attributes #1, Funkce (venkovní): Ne; Object Layer Attributes #1, Vážená stavební neprůzvučnost: 54; Object Layer Attributes #1, Vlhkostní namáhání oboustranné: Ne; Object Layer Attributes #1, Tloušťka opláštění: 2×12,5; Object Layer Attributes #1, Typ SDK desky: vysokopevnostní+bílá; Object Layer Attributes #1, Způsob opláštění: Oboustranné; Object Layer Attributes #1, Tloušťka izolace (2): 100; Object Layer Attributes #1, Objemová hmotnost izolace: 25; Object Layer Attributes #1, Typ profilu pro SDK: CW 100
Dveřní otvor | Půdorys 1.NP | Suché stavební práce | 1464Dve1096313847 | m3 | Stěna | NEW | 1.908 | 0.125 | 0.238 | 2.12 | 0.9 | NEMSOK - Object Layer Attributes #1, Směr otevírání dveří: L; Object Layer Attributes #1, Označení: Dveřní otvor; Object Layer Attributes #1, Kód prvku: SN07.03.0001; Object Layer Attributes #1, Podlaží: 1.NP; Object Layer Attributes #1, 2D interakce: yes; Object Layer Attributes #1, Staticky nosná konstrukce: no; Object Layer Attributes #1, Požární odolnost: EI 60; Object Layer Attributes #1, Statická funkce: Ne; Object Layer Attributes #1, Funkce (venkovní): Ne; Object Layer Attributes #1, Vážená stavební neprůzvučnost: 54; Object Layer Attributes #1, Vlhkostní namáhání oboustranné: Ne; Object Layer Attributes #1, Tloušťka opláštění: 2×12,5; Object Layer Attributes #1, Typ SDK desky: vysokopevnostní+bílá; Object Layer Attributes #1, Způsob opláštění: Oboustranné; Object Layer Attributes #1, Tloušťka izolace (2): 100; Object Layer Attributes #1, Objemová hmotnost izolace: 25; Object Layer Attributes #1, Typ profilu pro SDK: CW 100
Okenní otvor | Půdorys 1.NP | Suché stavební práce | 1464Okn1096313491 | m3 | Stěna | NEW | 0.72 | 0.125 | 0.09 | 1.2 | 0.6 | NEMSOK - Object Layer Attributes #1, Označení: Okenní otvor; Object Layer Attributes #1, Kód prvku: SN07.03.0001; Object Layer Attributes #1, Podlaží: 1.NP; Object Layer Attributes #1, 2D interakce: yes; Object Layer Attributes #1, Staticky nosná konstrukce: no; Object Layer Attributes #1, Požární odolnost: EI 60; Object Layer Attributes #1, Statická funkce: Ne; Object Layer Attributes #1, Funkce (venkovní): Ne; Object Layer Attributes #1, Vážená stavební neprůzvučnost: 54; Object Layer Attributes #1, Vlhkostní namáhání oboustranné: Ne; Object Layer Attributes #1, Tloušťka opláštění: 2×12,5; Object Layer Attributes #1, Typ SDK desky: vysokopevnostní+bílá; Object Layer Attributes #1, Způsob opláštění: Oboustranné; Object Layer Attributes #1, Tloušťka izolace (2): 100; Object Layer Attributes #1, Objemová hmotnost izolace: 25; Object Layer Attributes #1, Typ profilu pro SDK: CW 100
VZT | Půdorys 1.NP | Suché stavební práce | 1464SVý1096313840 | m3 | Stěna | NEW | 0.071 | 0.125 | 0.009 | 0.3 | 0.3 | NEMSOK - Object Layer Attributes #1, Označení: VZT; Object Layer Attributes #1, Kód prvku: SN07.03.0001; Object Layer Attributes #1, Podlaží: 1.NP; Object Layer Attributes #1, 2D interakce: yes; Object Layer Attributes #1, Staticky nosná konstrukce: no; Object Layer Attributes #1, Požární odolnost: EI 60; Object Layer Attributes #1, Statická funkce: Ne; Object Layer Attributes #1, Funkce (venkovní): Ne; Object Layer Attributes #1, Vážená stavební neprůzvučnost: 54; Object Layer Attributes #1, Vlhkostní namáhání oboustranné: Ne; Object Layer Attributes #1, Tloušťka opláštění: 2×12,5; Object Layer Attributes #1, Typ SDK desky: vysokopevnostní+bílá; Object Layer Attributes #1, Způsob opláštění: Oboustranné; Object Layer Attributes #1, Tloušťka izolace (2): 100; Object Layer Attributes #1, Objemová hmotnost izolace: 25; Object Layer Attributes #1, Typ profilu pro SDK: CW 100
VZT | Půdorys 1.NP | Suché stavební práce | 1464SVý1096313864 | m3 | Stěna | NEW | 0.053 | 0.125 | 0.007 | 0.26 | 0.26 | NEMSOK - Object Layer Attributes #1, Označení: VZT; Object Layer Attributes #1, Kód prvku: SN07.03.0001; Object Layer Attributes #1, Podlaží: 1.NP; Object Layer Attributes #1, 2D interakce: yes; Object Layer Attributes #1, Staticky nosná konstrukce: no; Object Layer Attributes #1, Požární odolnost: EI 60; Object Layer Attributes #1, Statická funkce: Ne; Object Layer Attributes #1, Funkce (venkovní): Ne; Object Layer Attributes #1, Vážená stavební neprůzvučnost: 54; Object Layer Attributes #1, Vlhkostní namáhání oboustranné: Ne; Object Layer Attributes #1, Tloušťka opláštění: 2×12,5; Object Layer Attributes #1, Typ SDK desky: vysokopevnostní+bílá; Object Layer Attributes #1, Způsob opláštění: Oboustranné; Object Layer Attributes #1, Tloušťka izolace (2): 100; Object Layer Attributes #1, Objemová hmotnost izolace: 25; Object Layer Attributes #1, Typ profilu pro SDK: CW 100
Dveřní otvor | Půdorys 1.NP | Suché stavební práce | 1464Dve1096313778 | m3 | Stěna | NEW | 1.696 | 0.1 | 0.17 | 2.12 | 0.8 | NEMSOK - Object Layer Attributes #1, Směr otevírání dveří: P; Object Layer Attributes #1, Označení: Dveřní otvor; Object Layer Attributes #1, Kód prvku: SN07.03.0001; Object Layer Attributes #1, Podlaží: 1.NP; Object Layer Attributes #1, 2D interakce: yes; Object Layer Attributes #1, Staticky nosná konstrukce: no; Object Layer Attributes #1, Požární odolnost: EI 60; Object Layer Attributes #1, Statická funkce: Ne; Object Layer Attributes #1, Funkce (venkovní): Ne; Object Layer Attributes #1, Vážená stavební neprůzvučnost: 54; Object Layer Attributes #1, Vlhkostní namáhání oboustranné: Ne; Object Layer Attributes #1, Tloušťka opláštění: 2×12,5; Object Layer Attributes #1, Typ SDK desky: vysokopevnostní+bílá; Object Layer Attributes #1, Způsob opláštění: Oboustranné; Object Layer Attributes #1, Tloušťka izolace (2): 100; Object Layer Attributes #1, Objemová hmotnost izolace: 25; Object Layer Attributes #1, Typ profilu pro SDK: CW 100
VZT | Půdorys 1.NP | Suché stavební práce | 1464SVý1096313788 | m3 | Stěna | NEW | 0.031 | 0.1 | 0.003 | 0.2 | 0.2 | NEMSOK - Object Layer Attributes #1, Označení: VZT; Object Layer Attributes #1, Kód prvku: SN07.03.0001; Object Layer Attributes #1, Podlaží: 1.NP; Object Layer Attributes #1, 2D interakce: yes; Object Layer Attributes #1, Staticky nosná konstrukce: no; Object Layer Attributes #1, Požární odolnost: EI 60; Object Layer Attributes #1, Statická funkce: Ne; Object Layer Attributes #1, Funkce (venkovní): Ne; Object Layer Attributes #1, Vážená stavební neprůzvučnost: 54; Object Layer Attributes #1, Vlhkostní namáhání oboustranné: Ne; Object Layer Attributes #1, Tloušťka opláštění: 2×12,5; Object Layer Attributes #1, Typ SDK desky: vysokopevnostní+bílá; Object Layer Attributes #1, Způsob opláštění: Oboustranné; Object Layer Attributes #1, Tloušťka izolace (2): 100; Object Layer Attributes #1, Objemová hmotnost izolace: 25; Object Layer Attributes #1, Typ profilu pro SDK: CW 100
Dveřní otvor | Půdorys 1.NP | Suché stavební práce | 1464Dve1096313825 | m3 | Stěna | NEW | 3.769 | 0.125 | 0.471 | 2.16 | 1.745 | NEMSOK - Object Layer Attributes #1, Směr otevírání dveří: L; Object Layer Attributes #1, Označení: Dveřní otvor; Object Layer Attributes #1, Kód prvku: SN07.03.0001; Object Layer Attributes #1, Podlaží: 1.NP; Object Layer Attributes #1, 2D interakce: yes; Object Layer Attributes #1, Staticky nosná konstrukce: no; Object Layer Attributes #1, Požární odolnost: EI 60; Object Layer Attributes #1, Statická funkce: Ne; Object Layer Attributes #1, Funkce (venkovní): Ne; Object Layer Attributes #1, Vážená stavební neprůzvučnost: 54; Object Layer Attributes #1, Vlhkostní namáhání oboustranné: Ne; Object Layer Attributes #1, Tloušťka opláštění: 2×12,5; Object Layer Attributes #1, Typ SDK desky: vysokopevnostní+bílá; Object Layer Attributes #1, Způsob opláštění: Oboustranné; Object Layer Attributes #1, Tloušťka izolace (2): 100; Object Layer Attributes #1, Objemová hmotnost izolace: 25; Object Layer Attributes #1, Typ profilu pro SDK: CW 100
VZT | Půdorys 1.NP | Suché stavební práce | 1464SVý1096313822 | m3 | Stěna | NEW | 0.053 | 0.125 | 0.007 | 0.26 | 0.26 | NEMSOK - Object Layer Attributes #1, Označení: VZT; Object Layer Attributes #1, Kód prvku: SN07.03.0001; Object Layer Attributes #1, Podlaží: 1.NP; Object Layer Attributes #1, 2D interakce: yes; Object Layer Attributes #1, Staticky nosná konstrukce: no; Object Layer Attributes #1, Požární odolnost: EI 60; Object Layer Attributes #1, Statická funkce: Ne; Object Layer Attributes #1, Funkce (venkovní): Ne; Object Layer Attributes #1, Vážená stavební neprůzvučnost: 54; Object Layer Attributes #1, Vlhkostní namáhání oboustranné: Ne; Object Layer Attributes #1, Tloušťka opláštění: 2×12,5; Object Layer Attributes #1, Typ SDK desky: vysokopevnostní+bílá; Object Layer Attributes #1, Způsob opláštění: Oboustranné; Object Layer Attributes #1, Tloušťka izolace (2): 100; Object Layer Attributes #1, Objemová hmotnost izolace: 25; Object Layer Attributes #1, Typ profilu pro SDK: CW 100
VZT | Půdorys 1.NP | Suché stavební práce | 1464SVý1096314288 | m3 | Stěna | NEW | 0.105 | 0.1 | 0.011 | 0.3 | 0.35 | NEMSOK - Object Layer Attributes #1, Označení: VZT; Object Layer Attributes #1, Kód prvku: SN07.03.0001; Object Layer Attributes #1, Podlaží: 1.NP; Object Layer Attributes #1, 2D interakce: yes; Object Layer Attributes #1, Staticky nosná konstrukce: no; Object Layer Attributes #1, Požární odolnost: EI 60; Object Layer Attributes #1, Statická funkce: Ne; Object Layer Attributes #1, Vnější průměr: 1010431516015xxxxxxx0; Object Layer Attributes #1, Funkce (venkovní): Ne; Object Layer Attributes #1, Vážená stavební neprůzvučnost: 54; Object Layer Attributes #1, Vlhkostní namáhání oboustranné: Ne; Object Layer Attributes #1, Tloušťka opláštění: 2×12,5; Object Layer Attributes #1, Typ SDK desky: vysokopevnostní+bílá; Object Layer Attributes #1, Způsob opláštění: Oboustranné; Object Layer Attributes #1, Tloušťka izolace (2): 100; Object Layer Attributes #1, Objemová hmotnost izolace: 25; Object Layer Attributes #1, Typ profilu pro SDK: CW 100
VZT | Půdorys 1.NP | Suché stavební práce | 1464SVý1096313578 | m3 | Stěna | NEW | 0.071 | 0.15 | 0.011 | 0.3 | 0.3 | NEMSOK - Object Layer Attributes #1, Označení: VZT; Object Layer Attributes #1, Kód prvku: SN07.03.0001; Object Layer Attributes #1, Podlaží: 1.NP; Object Layer Attributes #1, 2D interakce: yes; Object Layer Attributes #1, Staticky nosná konstrukce: no; Object Layer Attributes #1, Požární odolnost: EI 60; Object Layer Attributes #1, Statická funkce: Ne; Object Layer Attributes #1, Funkce (venkovní): Ne; Object Layer Attributes #1, Vážená stavební neprůzvučnost: 54; Object Layer Attributes #1, Vlhkostní namáhání oboustranné: Ne; Object Layer Attributes #1, Tloušťka opláštění: 2×12,5; Object Layer Attributes #1, Typ SDK desky: vysokopevnostní+bílá; Object Layer Attributes #1, Způsob opláštění: Oboustranné; Object Layer Attributes #1, Tloušťka izolace (2): 100; Object Layer Attributes #1, Objemová hmotnost izolace: 25; Object Layer Attributes #1, Typ profilu pro SDK: CW 100
VZT | Půdorys 1.NP | Suché stavební práce | 1464SVý1096313583 | m3 | Stěna | NEW | 0.071 | 0.15 | 0.011 | 0.3 | 0.3 | NEMSOK - Object Layer Attributes #1, Označení: VZT; Object Layer Attributes #1, Kód prvku: SN07.03.0001; Object Layer Attributes #1, Podlaží: 1.NP; Object Layer Attributes #1, 2D interakce: yes; Object Layer Attributes #1, Staticky nosná konstrukce: no; Object Layer Attributes #1, Požární odolnost: EI 60; Object Layer Attributes #1, Statická funkce: Ne; Object Layer Attributes #1, Funkce (venkovní): Ne; Object Layer Attributes #1, Vážená stavební neprůzvučnost: 54; Object Layer Attributes #1, Vlhkostní namáhání oboustranné: Ne; Object Layer Attributes #1, Tloušťka opláštění: 2×12,5; Object Layer Attributes #1, Typ SDK desky: vysokopevnostní+bílá; Object Layer Attributes #1, Způsob opláštění: Oboustranné; Object Layer Attributes #1, Tloušťka izolace (2): 100; Object Layer Attributes #1, Objemová hmotnost izolace: 25; Object Layer Attributes #1, Typ profilu pro SDK: CW 100
Dveřní otvor | Půdorys 1.NP | Suché stavební práce | 1464Dve1096312995 | m3 | Stěna | NEW | 2.205 | 0.125 | 0.276 | 2.45 | 0.9 | NEMSOK - Object Layer Attributes #1, Směr otevírání dveří: L; Object Layer Attributes #1, Označení: Dveřní otvor; Object Layer Attributes #1, Kód prvku: SN07.03.0001; Object Layer Attributes #1, Podlaží: 1.NP; Object Layer Attributes #1, 2D interakce: yes; Object Layer Attributes #1, Staticky nosná konstrukce: no; Object Layer Attributes #1, Požární odolnost: EI 60; Object Layer Attributes #1, Statická funkce: Ne; Object Layer Attributes #1, Funkce (venkovní): Ne; Object Layer Attributes #1, Vážená stavební neprůzvučnost: 54; Object Layer Attributes #1, Vlhkostní namáhání oboustranné: Ne; Object Layer Attributes #1, Tloušťka opláštění: 2×12,5; Object Layer Attributes #1, Typ SDK desky: vysokopevnostní+bílá; Object Layer Attributes #1, Způsob opláštění: Oboustranné; Object Layer Attributes #1, Tloušťka izolace (2): 100; Object Layer Attributes #1, Objemová hmotnost izolace: 25; Object Layer Attributes #1, Typ profilu pro SDK: CW 100
VZT | Půdorys 1.NP | Suché stavební práce | 1464SVý1096313876 | m3 | Stěna | NEW | 0.15 | 0.2 | 0.03 | 0.3 | 0.5 | NEMSOK - Object Layer Attributes #1, Označení: VZT; Object Layer Attributes #1, Kód prvku: SN07.03.0001; Object Layer Attributes #1, Podlaží: 1.NP; Object Layer Attributes #1, 2D interakce: yes; Object Layer Attributes #1, Staticky nosná konstrukce: no; Object Layer Attributes #1, Požární odolnost: EI 60; Object Layer Attributes #1, Statická funkce: Ne; Object Layer Attributes #1, Vnější průměr: 1010431516015xxxxxxx0; Object Layer Attributes #1, Funkce (venkovní): Ne; Object Layer Attributes #1, Vážená stavební neprůzvučnost: 54; Object Layer Attributes #1, Vlhkostní namáhání oboustranné: Ne; Object Layer Attributes #1, Tloušťka opláštění: 2×12,5; Object Layer Attributes #1, Typ SDK desky: vysokopevnostní+bílá; Object Layer Attributes #1, Způsob opláštění: Oboustranné; Object Layer Attributes #1, Tloušťka izolace (2): 100; Object Layer Attributes #1, Objemová hmotnost izolace: 25; Object Layer Attributes #1, Typ profilu pro SDK: CW 100
Okenní otvor | Půdorys 1.NP | Suché stavební práce | 1464Okn1096313498 | m3 | Stěna | NEW | 0.72 | 0.1 | 0.072 | 1.2 | 0.6 | NEMSOK - Object Layer Attributes #1, Označení: Okenní otvor; Object Layer Attributes #1, Kód prvku: SN07.03.0001; Object Layer Attributes #1, Podlaží: 1.NP; Object Layer Attributes #1, 2D interakce: yes; Object Layer Attributes #1, Staticky nosná konstrukce: no; Object Layer Attributes #1, Požární odolnost: EI 60; Object Layer Attributes #1, Statická funkce: Ne; Object Layer Attributes #1, Funkce (venkovní): Ne; Object Layer Attributes #1, Vážená stavební neprůzvučnost: 54; Object Layer Attributes #1, Vlhkostní namáhání oboustranné: Ne; Object Layer Attributes #1, Tloušťka opláštění: 2×12,5; Object Layer Attributes #1, Typ SDK desky: vysokopevnostní+bílá; Object Layer Attributes #1, Způsob opláštění: Oboustranné; Object Layer Attributes #1, Tloušťka izolace (2): 100; Object Layer Attributes #1, Objemová hmotnost izolace: 25; Object Layer Attributes #1, Typ profilu pro SDK: CW 100
Dveřní otvor | Půdorys 1.NP | Suché stavební práce | 1464Dve1096314250 | m3 | Stěna | NEW | 3.6 | 0.25 | 0.9 | 2.4 | 1.5 | NEMSOK - Object Layer Attributes #1, Směr otevírání dveří: -; Object Layer Attributes #1, Označení: Dveřní otvor; Object Layer Attributes #1, Kód prvku: SN07.03.0001; Object Layer Attributes #1, Podlaží: 1.NP; Object Layer Attributes #1, 2D interakce: yes; Object Layer Attributes #1, Staticky nosná konstrukce: no; Object Layer Attributes #1, Požární odolnost: EI 60; Object Layer Attributes #1, Statická funkce: Ne; Object Layer Attributes #1, Funkce (venkovní): Ne; Object Layer Attributes #1, Vážená stavební neprůzvučnost: 54; Object Layer Attributes #1, Vlhkostní namáhání oboustranné: Ne; Object Layer Attributes #1, Tloušťka opláštění: 2×12,5; Object Layer Attributes #1, Typ SDK desky: vysokopevnostní+bílá; Object Layer Attributes #1, Způsob opláštění: Oboustranné; Object Layer Attributes #1, Tloušťka izolace (2): 100; Object Layer Attributes #1, Objemová hmotnost izolace: 25; Object Layer Attributes #1, Typ profilu pro SDK: CW 100
Stěnová nika | Půdorys 1.NP | Suché stavební práce | 1464SNi1096313540 | m3 | Stěnová nika | NEW | 0.04 | 0.05 | 0.002 | 0.2 | 0.2 | NEMSOK - Object Layer Attributes #1, Označení: Stěnová nika
Stěnová nika | Půdorys 1.NP | Suché stavební práce | 1464SNi1096313546 | m3 | Stěna | NEW | 0.25 | 0.05 | 0.013 | 0.5 | 0.5 | NEMSOK - Object Layer Attributes #1, Označení: Stěnová nika; Object Layer Attributes #1, Kód prvku: SN07.03.0001; Object Layer Attributes #1, Podlaží: 1.NP; Object Layer Attributes #1, 2D interakce: yes; Object Layer Attributes #1, Staticky nosná konstrukce: no; Object Layer Attributes #1, Požární odolnost: EI 60; Object Layer Attributes #1, Statická funkce: Ne; Object Layer Attributes #1, Funkce (venkovní): Ne; Object Layer Attributes #1, Vážená stavební neprůzvučnost: 54; Object Layer Attributes #1, Vlhkostní namáhání oboustranné: Ne; Object Layer Attributes #1, Tloušťka opláštění: 2×12,5; Object Layer Attributes #1, Typ SDK desky: vysokopevnostní+bílá; Object Layer Attributes #1, Způsob opláštění: Oboustranné; Object Layer Attributes #1, Tloušťka izolace (2): 100; Object Layer Attributes #1, Objemová hmotnost izolace: 25; Object Layer Attributes #1, Typ profilu pro SDK: CW 100
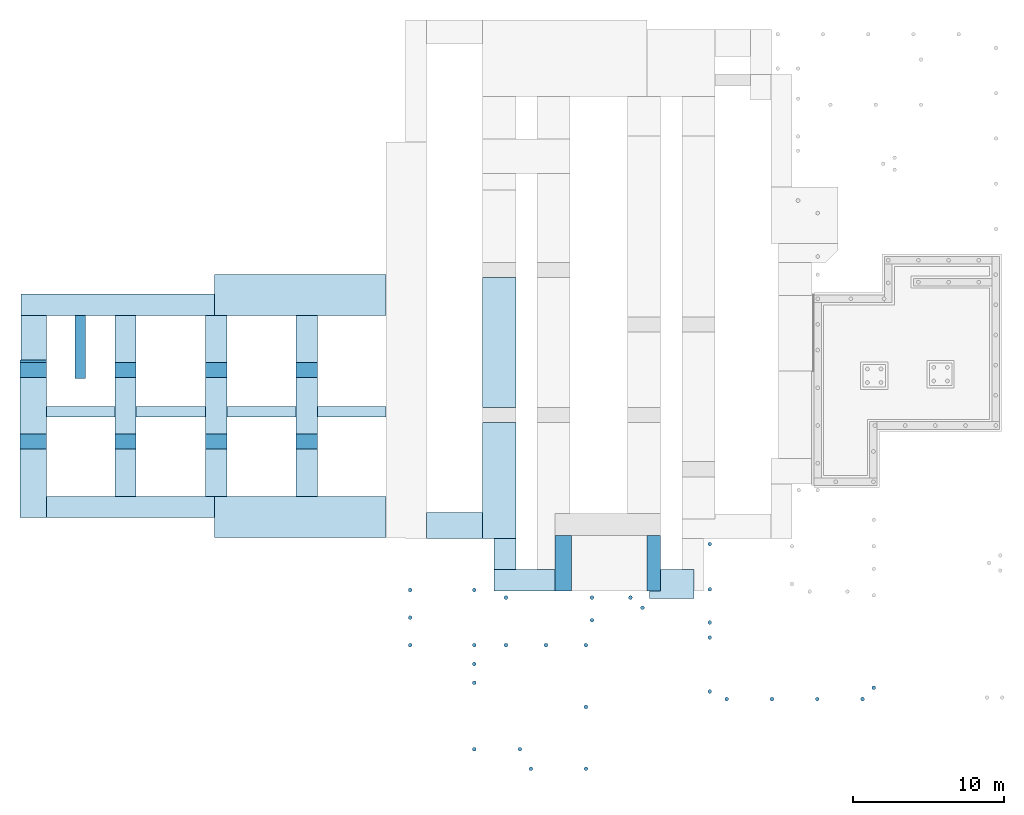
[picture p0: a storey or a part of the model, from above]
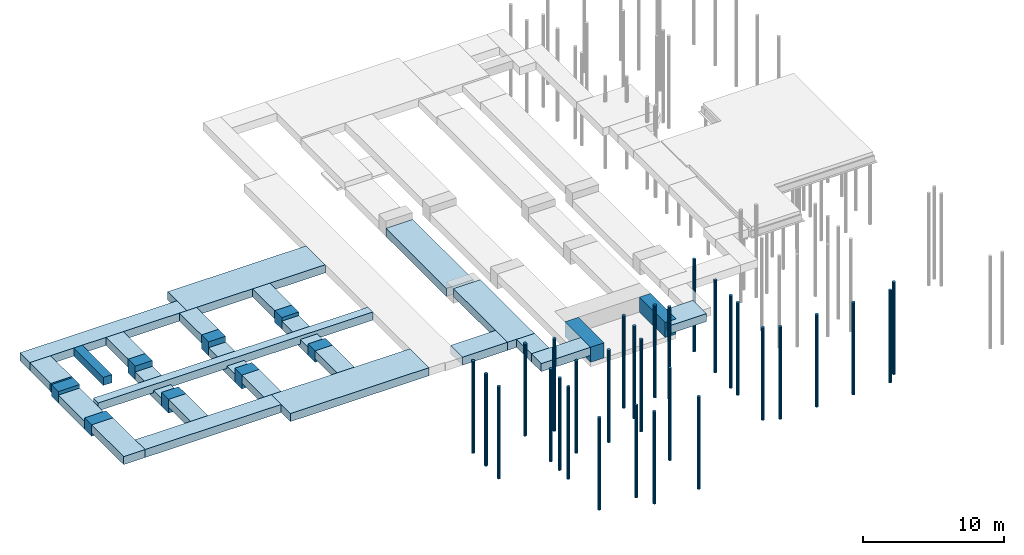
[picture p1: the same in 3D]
Properties of the parts of a building model (IFC4), part 17 of 45

# IfcOpeningElement: Opening (1638)
Name | In | Object Layer Attributes #1, Práce | Object Layer Attributes #1, Allright_Stavebni_dil_ID | Object Layer Attributes #1, Jednotka | Object Layer Attributes #1, Název_objektu | Status | Area (m2) | Depth (m) | Volume (m3) | Height (m) | Width (m)
VZT | Půdorys 1.NP | Suché stavební práce | 1464SVý1096314253 | m3 | Stěna | NEW | 0.114 | 0.25 | 0.028 | 0.3 | 0.38 | NEMSOK - Object Layer Attributes #1, Označení: VZT; Object Layer Attributes #1, Kód prvku: SN07.03.0001; Object Layer Attributes #1, Podlaží: 1.NP; Object Layer Attributes #1, 2D interakce: yes; Object Layer Attributes #1, Staticky nosná konstrukce: no; Object Layer Attributes #1, Požární odolnost: EI 60; Object Layer Attributes #1, Statická funkce: Ne; Object Layer Attributes #1, Vnější průměr: 1010431516015xxxxxxx0; Object Layer Attributes #1, Funkce (venkovní): Ne; Object Layer Attributes #1, Vážená stavební neprůzvučnost: 54; Object Layer Attributes #1, Vlhkostní namáhání oboustranné: Ne; Object Layer Attributes #1, Tloušťka opláštění: 2×12,5; Object Layer Attributes #1, Typ SDK desky: vysokopevnostní+bílá; Object Layer Attributes #1, Způsob opláštění: Oboustranné; Object Layer Attributes #1, Tloušťka izolace (2): 100; Object Layer Attributes #1, Objemová hmotnost izolace: 25; Object Layer Attributes #1, Typ profilu pro SDK: CW 100
VZT | Půdorys 1.NP | Suché stavební práce | 1464SVý1096314265 | m3 | Stěnový výklenek |  | 0.114 | 0.25 | 0.028 | 0.3 | 0.38 | NEMSOK - Object Layer Attributes #1, Označení: VZT; Object Layer Attributes #1, Vnější průměr: 1010431516015xxxxxxx0
VZT | Půdorys 1.NP | Suché stavební práce | 1464SVý1096314203 | m3 | Stěna | NEW | 0.165 | 0.15 | 0.025 | 0.3 | 0.55 | NEMSOK - Object Layer Attributes #1, Označení: VZT; Object Layer Attributes #1, Kód prvku: SN07.03.0001; Object Layer Attributes #1, Podlaží: 1.NP; Object Layer Attributes #1, 2D interakce: yes; Object Layer Attributes #1, Staticky nosná konstrukce: no; Object Layer Attributes #1, Požární odolnost: EI 60; Object Layer Attributes #1, Statická funkce: Ne; Object Layer Attributes #1, Vnější průměr: 1010431516015xxxxxxx0; Object Layer Attributes #1, Funkce (venkovní): Ne; Object Layer Attributes #1, Vážená stavební neprůzvučnost: 54; Object Layer Attributes #1, Vlhkostní namáhání oboustranné: Ne; Object Layer Attributes #1, Tloušťka opláštění: 2×12,5; Object Layer Attributes #1, Typ SDK desky: vysokopevnostní+bílá; Object Layer Attributes #1, Způsob opláštění: Oboustranné; Object Layer Attributes #1, Tloušťka izolace (2): 100; Object Layer Attributes #1, Objemová hmotnost izolace: 25; Object Layer Attributes #1, Typ profilu pro SDK: CW 100
Stěnová nika | Půdorys 1.NP | Suché stavební práce | 1464SNi1096313058 | m3 | Stěna | NEW | 0.422 | 0.175 | 0.074 | 0.65 | 0.65 | NEMSOK - Object Layer Attributes #1, Označení: Stěnová nika; Object Layer Attributes #1, Kód prvku: SN07.03.0001; Object Layer Attributes #1, Podlaží: 1.NP; Object Layer Attributes #1, 2D interakce: yes; Object Layer Attributes #1, Staticky nosná konstrukce: no; Object Layer Attributes #1, Požární odolnost: EI 60; Object Layer Attributes #1, Statická funkce: Ne; Object Layer Attributes #1, Funkce (venkovní): Ne; Object Layer Attributes #1, Vážená stavební neprůzvučnost: 54; Object Layer Attributes #1, Vlhkostní namáhání oboustranné: Ne; Object Layer Attributes #1, Tloušťka opláštění: 2×12,5; Object Layer Attributes #1, Typ SDK desky: vysokopevnostní+bílá; Object Layer Attributes #1, Způsob opláštění: Oboustranné; Object Layer Attributes #1, Tloušťka izolace (2): 100; Object Layer Attributes #1, Objemová hmotnost izolace: 25; Object Layer Attributes #1, Typ profilu pro SDK: CW 100
VZT | Půdorys 1.NP | Suché stavební práce | 1464SVý1096314225 | m3 | Stěna | NEW | 0.038 | 0.15 | 0.006 | 0.22 | 0.22 | NEMSOK - Object Layer Attributes #1, Označení: VZT; Object Layer Attributes #1, Kód prvku: SN07.03.0001; Object Layer Attributes #1, Podlaží: 1.NP; Object Layer Attributes #1, 2D interakce: yes; Object Layer Attributes #1, Staticky nosná konstrukce: no; Object Layer Attributes #1, Požární odolnost: EI 60; Object Layer Attributes #1, Statická funkce: Ne; Object Layer Attributes #1, Funkce (venkovní): Ne; Object Layer Attributes #1, Vážená stavební neprůzvučnost: 54; Object Layer Attributes #1, Vlhkostní namáhání oboustranné: Ne; Object Layer Attributes #1, Tloušťka opláštění: 2×12,5; Object Layer Attributes #1, Typ SDK desky: vysokopevnostní+bílá; Object Layer Attributes #1, Způsob opláštění: Oboustranné; Object Layer Attributes #1, Tloušťka izolace (2): 100; Object Layer Attributes #1, Objemová hmotnost izolace: 25; Object Layer Attributes #1, Typ profilu pro SDK: CW 100
VZT | Půdorys 1.NP | Suché stavební práce | 1464SVý1096314239 | m3 | Stěna | NEW | 0.18 | 0.15 | 0.027 | 0.3 | 0.6 | NEMSOK - Object Layer Attributes #1, Označení: VZT; Object Layer Attributes #1, Kód prvku: SN07.03.0001; Object Layer Attributes #1, Podlaží: 1.NP; Object Layer Attributes #1, 2D interakce: yes; Object Layer Attributes #1, Staticky nosná konstrukce: no; Object Layer Attributes #1, Požární odolnost: EI 60; Object Layer Attributes #1, Statická funkce: Ne; Object Layer Attributes #1, Vnější průměr: 1010431516015xxxxxxx0; Object Layer Attributes #1, Funkce (venkovní): Ne; Object Layer Attributes #1, Vážená stavební neprůzvučnost: 54; Object Layer Attributes #1, Vlhkostní namáhání oboustranné: Ne; Object Layer Attributes #1, Tloušťka opláštění: 2×12,5; Object Layer Attributes #1, Typ SDK desky: vysokopevnostní+bílá; Object Layer Attributes #1, Způsob opláštění: Oboustranné; Object Layer Attributes #1, Tloušťka izolace (2): 100; Object Layer Attributes #1, Objemová hmotnost izolace: 25; Object Layer Attributes #1, Typ profilu pro SDK: CW 100
VZT | Půdorys 1.NP | Suché stavební práce | 1464SVý1096314504 | m3 | Stěna | NEW | 0.049 | 0.15 | 0.007 | 0.25 | 0.25 | NEMSOK - Object Layer Attributes #1, Označení: VZT; Object Layer Attributes #1, Kód prvku: SN07.03.0001; Object Layer Attributes #1, Podlaží: 1.NP; Object Layer Attributes #1, 2D interakce: yes; Object Layer Attributes #1, Staticky nosná konstrukce: no; Object Layer Attributes #1, Požární odolnost: EI 60; Object Layer Attributes #1, Statická funkce: Ne; Object Layer Attributes #1, Funkce (venkovní): Ne; Object Layer Attributes #1, Vážená stavební neprůzvučnost: 54; Object Layer Attributes #1, Vlhkostní namáhání oboustranné: Ne; Object Layer Attributes #1, Tloušťka opláštění: 2×12,5; Object Layer Attributes #1, Typ SDK desky: vysokopevnostní+bílá; Object Layer Attributes #1, Způsob opláštění: Oboustranné; Object Layer Attributes #1, Tloušťka izolace (2): 100; Object Layer Attributes #1, Objemová hmotnost izolace: 25; Object Layer Attributes #1, Typ profilu pro SDK: CW 100
VZT+ZTI | Půdorys 1.NP | Suché stavební práce | 1464SVý1096314714 | m3 | Stěna | NEW | 0.095 | 0.15 | 0.014 | 0.265 | 0.36 | NEMSOK - Object Layer Attributes #1, Označení: VZT+ZTI; Object Layer Attributes #1, Kód prvku: SN07.03.0001; Object Layer Attributes #1, Podlaží: 1.NP; Object Layer Attributes #1, 2D interakce: yes; Object Layer Attributes #1, Staticky nosná konstrukce: no; Object Layer Attributes #1, Požární odolnost: EI 60; Object Layer Attributes #1, Statická funkce: Ne; Object Layer Attributes #1, Vnější průměr: 1010431516015xxxxxxx0; Object Layer Attributes #1, Funkce (venkovní): Ne; Object Layer Attributes #1, Vážená stavební neprůzvučnost: 54; Object Layer Attributes #1, Vlhkostní namáhání oboustranné: Ne; Object Layer Attributes #1, Tloušťka opláštění: 2×12,5; Object Layer Attributes #1, Typ SDK desky: vysokopevnostní+bílá; Object Layer Attributes #1, Způsob opláštění: Oboustranné; Object Layer Attributes #1, Tloušťka izolace (2): 100; Object Layer Attributes #1, Objemová hmotnost izolace: 25; Object Layer Attributes #1, Typ profilu pro SDK: CW 100
VZT | Půdorys 1.NP | Suché stavební práce | 1464SVý1096314315 | m3 | Stěna | NEW | 0.096 | 0.15 | 0.014 | 0.35 | 0.35 | NEMSOK - Object Layer Attributes #1, Označení: VZT; Object Layer Attributes #1, Kód prvku: SN07.03.0001; Object Layer Attributes #1, Podlaží: 1.NP; Object Layer Attributes #1, 2D interakce: yes; Object Layer Attributes #1, Staticky nosná konstrukce: no; Object Layer Attributes #1, Požární odolnost: EI 60; Object Layer Attributes #1, Statická funkce: Ne; Object Layer Attributes #1, Funkce (venkovní): Ne; Object Layer Attributes #1, Vážená stavební neprůzvučnost: 54; Object Layer Attributes #1, Vlhkostní namáhání oboustranné: Ne; Object Layer Attributes #1, Tloušťka opláštění: 2×12,5; Object Layer Attributes #1, Typ SDK desky: vysokopevnostní+bílá; Object Layer Attributes #1, Způsob opláštění: Oboustranné; Object Layer Attributes #1, Tloušťka izolace (2): 100; Object Layer Attributes #1, Objemová hmotnost izolace: 25; Object Layer Attributes #1, Typ profilu pro SDK: CW 100
Stěnová nika | Půdorys 1.NP | Suché stavební práce | 1464SNi1096313534 | m3 | Stěna | NEW | 0.03 | 0.05 | 0.002 | 0.2 | 0.15 | NEMSOK - Object Layer Attributes #1, Označení: Stěnová nika; Object Layer Attributes #1, Kód prvku: SN07.03.0001; Object Layer Attributes #1, Podlaží: 1.NP; Object Layer Attributes #1, 2D interakce: yes; Object Layer Attributes #1, Staticky nosná konstrukce: no; Object Layer Attributes #1, Požární odolnost: EI 60; Object Layer Attributes #1, Statická funkce: Ne; Object Layer Attributes #1, Funkce (venkovní): Ne; Object Layer Attributes #1, Vážená stavební neprůzvučnost: 54; Object Layer Attributes #1, Vlhkostní namáhání oboustranné: Ne; Object Layer Attributes #1, Tloušťka opláštění: 2×12,5; Object Layer Attributes #1, Typ SDK desky: vysokopevnostní+bílá; Object Layer Attributes #1, Způsob opláštění: Oboustranné; Object Layer Attributes #1, Tloušťka izolace (2): 100; Object Layer Attributes #1, Objemová hmotnost izolace: 25; Object Layer Attributes #1, Typ profilu pro SDK: CW 100
VZT | Půdorys 1.NP | Suché stavební práce | 1464SVý1096314183 | m3 | Stěna | NEW | 0.165 | 0.15 | 0.025 | 0.3 | 0.55 | NEMSOK - Object Layer Attributes #1, Označení: VZT; Object Layer Attributes #1, Kód prvku: SN07.03.0001; Object Layer Attributes #1, Podlaží: 1.NP; Object Layer Attributes #1, 2D interakce: yes; Object Layer Attributes #1, Staticky nosná konstrukce: no; Object Layer Attributes #1, Požární odolnost: EI 60; Object Layer Attributes #1, Statická funkce: Ne; Object Layer Attributes #1, Vnější průměr: 1010431516015xxxxxxx0; Object Layer Attributes #1, Funkce (venkovní): Ne; Object Layer Attributes #1, Vážená stavební neprůzvučnost: 54; Object Layer Attributes #1, Vlhkostní namáhání oboustranné: Ne; Object Layer Attributes #1, Tloušťka opláštění: 2×12,5; Object Layer Attributes #1, Typ SDK desky: vysokopevnostní+bílá; Object Layer Attributes #1, Způsob opláštění: Oboustranné; Object Layer Attributes #1, Tloušťka izolace (2): 100; Object Layer Attributes #1, Objemová hmotnost izolace: 25; Object Layer Attributes #1, Typ profilu pro SDK: CW 100
VZT | Půdorys 1.NP | Suché stavební práce | 1464SVý1096313562 | m3 | Stěna | NEW | 0.04 | 0.15 | 0.006 | 0.225 | 0.225 | NEMSOK - Object Layer Attributes #1, Označení: VZT; Object Layer Attributes #1, Kód prvku: SN07.03.0001; Object Layer Attributes #1, Podlaží: 1.NP; Object Layer Attributes #1, 2D interakce: yes; Object Layer Attributes #1, Staticky nosná konstrukce: no; Object Layer Attributes #1, Požární odolnost: EI 60; Object Layer Attributes #1, Statická funkce: Ne; Object Layer Attributes #1, Funkce (venkovní): Ne; Object Layer Attributes #1, Vážená stavební neprůzvučnost: 54; Object Layer Attributes #1, Vlhkostní namáhání oboustranné: Ne; Object Layer Attributes #1, Tloušťka opláštění: 2×12,5; Object Layer Attributes #1, Typ SDK desky: vysokopevnostní+bílá; Object Layer Attributes #1, Způsob opláštění: Oboustranné; Object Layer Attributes #1, Tloušťka izolace (2): 100; Object Layer Attributes #1, Objemová hmotnost izolace: 25; Object Layer Attributes #1, Typ profilu pro SDK: CW 100
VZT | Půdorys 1.NP | Suché stavební práce | 1464SVý1096313568 | m3 | Stěna | NEW | 0.04 | 0.15 | 0.006 | 0.225 | 0.225 | NEMSOK - Object Layer Attributes #1, Označení: VZT; Object Layer Attributes #1, Kód prvku: SN07.03.0001; Object Layer Attributes #1, Podlaží: 1.NP; Object Layer Attributes #1, 2D interakce: yes; Object Layer Attributes #1, Staticky nosná konstrukce: no; Object Layer Attributes #1, Požární odolnost: EI 60; Object Layer Attributes #1, Statická funkce: Ne; Object Layer Attributes #1, Funkce (venkovní): Ne; Object Layer Attributes #1, Vážená stavební neprůzvučnost: 54; Object Layer Attributes #1, Vlhkostní namáhání oboustranné: Ne; Object Layer Attributes #1, Tloušťka opláštění: 2×12,5; Object Layer Attributes #1, Typ SDK desky: vysokopevnostní+bílá; Object Layer Attributes #1, Způsob opláštění: Oboustranné; Object Layer Attributes #1, Tloušťka izolace (2): 100; Object Layer Attributes #1, Objemová hmotnost izolace: 25; Object Layer Attributes #1, Typ profilu pro SDK: CW 100
VZT | Půdorys 1.NP | Suché stavební práce | 1464SVý1096313731 | m3 | Stěna | NEW | 0.071 | 0.125 | 0.009 | 0.3 | 0.3 | NEMSOK - Object Layer Attributes #1, Označení: VZT; Object Layer Attributes #1, Kód prvku: SN07.03.0001; Object Layer Attributes #1, Podlaží: 1.NP; Object Layer Attributes #1, 2D interakce: yes; Object Layer Attributes #1, Staticky nosná konstrukce: no; Object Layer Attributes #1, Požární odolnost: EI 60; Object Layer Attributes #1, Statická funkce: Ne; Object Layer Attributes #1, Funkce (venkovní): Ne; Object Layer Attributes #1, Vážená stavební neprůzvučnost: 54; Object Layer Attributes #1, Vlhkostní namáhání oboustranné: Ne; Object Layer Attributes #1, Tloušťka opláštění: 2×12,5; Object Layer Attributes #1, Typ SDK desky: vysokopevnostní+bílá; Object Layer Attributes #1, Způsob opláštění: Oboustranné; Object Layer Attributes #1, Tloušťka izolace (2): 100; Object Layer Attributes #1, Objemová hmotnost izolace: 25; Object Layer Attributes #1, Typ profilu pro SDK: CW 100
Dveřní otvor | Půdorys 1.NP | Suché stavební práce | 1464Dve1096313710 | m3 | Stěna | NEW | 1.908 | 0.125 | 0.238 | 2.12 | 0.9 | NEMSOK - Object Layer Attributes #1, Směr otevírání dveří: P; Object Layer Attributes #1, Označení: Dveřní otvor; Object Layer Attributes #1, Kód prvku: SN07.03.0001; Object Layer Attributes #1, Podlaží: 1.NP; Object Layer Attributes #1, 2D interakce: yes; Object Layer Attributes #1, Staticky nosná konstrukce: no; Object Layer Attributes #1, Požární odolnost: EI 60; Object Layer Attributes #1, Statická funkce: Ne; Object Layer Attributes #1, Funkce (venkovní): Ne; Object Layer Attributes #1, Vážená stavební neprůzvučnost: 54; Object Layer Attributes #1, Vlhkostní namáhání oboustranné: Ne; Object Layer Attributes #1, Tloušťka opláštění: 2×12,5; Object Layer Attributes #1, Typ SDK desky: vysokopevnostní+bílá; Object Layer Attributes #1, Způsob opláštění: Oboustranné; Object Layer Attributes #1, Tloušťka izolace (2): 100; Object Layer Attributes #1, Objemová hmotnost izolace: 25; Object Layer Attributes #1, Typ profilu pro SDK: CW 100
Dveřní otvor | Půdorys 1.NP | Suché stavební práce | 1464Dve1096313358 | m3 | Stěna | NEW | 1.6 | 0.125 | 0.2 | 2 | 0.8 | NEMSOK - Object Layer Attributes #1, Směr otevírání dveří: -; Object Layer Attributes #1, Označení: Dveřní otvor; Object Layer Attributes #1, Kód prvku: SN07.03.0001; Object Layer Attributes #1, Podlaží: 1.NP; Object Layer Attributes #1, 2D interakce: yes; Object Layer Attributes #1, Staticky nosná konstrukce: no; Object Layer Attributes #1, Požární odolnost: EI 60; Object Layer Attributes #1, Statická funkce: Ne; Object Layer Attributes #1, Funkce (venkovní): Ne; Object Layer Attributes #1, Vážená stavební neprůzvučnost: 54; Object Layer Attributes #1, Vlhkostní namáhání oboustranné: Ne; Object Layer Attributes #1, Tloušťka opláštění: 2×12,5; Object Layer Attributes #1, Typ SDK desky: vysokopevnostní+bílá; Object Layer Attributes #1, Způsob opláštění: Oboustranné; Object Layer Attributes #1, Tloušťka izolace (2): 100; Object Layer Attributes #1, Objemová hmotnost izolace: 25; Object Layer Attributes #1, Typ profilu pro SDK: CW 100
VZT | Půdorys 1.NP | Suché stavební práce | 1464SVý1096314044 | m3 | Stěna | NEW | 0.165 | 0.125 | 0.021 | 0.3 | 0.55 | NEMSOK - Object Layer Attributes #1, Označení: VZT; Object Layer Attributes #1, Kód prvku: SN07.03.0001; Object Layer Attributes #1, Podlaží: 1.NP; Object Layer Attributes #1, 2D interakce: yes; Object Layer Attributes #1, Staticky nosná konstrukce: no; Object Layer Attributes #1, Požární odolnost: EI 60; Object Layer Attributes #1, Statická funkce: Ne; Object Layer Attributes #1, Vnější průměr: 1010431516015xxxxxxx0; Object Layer Attributes #1, Funkce (venkovní): Ne; Object Layer Attributes #1, Vážená stavební neprůzvučnost: 54; Object Layer Attributes #1, Vlhkostní namáhání oboustranné: Ne; Object Layer Attributes #1, Tloušťka opláštění: 2×12,5; Object Layer Attributes #1, Typ SDK desky: vysokopevnostní+bílá; Object Layer Attributes #1, Způsob opláštění: Oboustranné; Object Layer Attributes #1, Tloušťka izolace (2): 100; Object Layer Attributes #1, Objemová hmotnost izolace: 25; Object Layer Attributes #1, Typ profilu pro SDK: CW 100
CHL | Půdorys 1.NP | Suché stavební práce | 1464SVý1096314052 | m3 | Stěna | NEW | 0.015 | 0.125 | 0.002 | 0.15 | 0.1 | NEMSOK - Object Layer Attributes #1, Označení: CHL; Object Layer Attributes #1, Kód prvku: SN07.03.0001; Object Layer Attributes #1, Podlaží: 1.NP; Object Layer Attributes #1, 2D interakce: yes; Object Layer Attributes #1, Staticky nosná konstrukce: no; Object Layer Attributes #1, Požární odolnost: EI 60; Object Layer Attributes #1, Statická funkce: Ne; Object Layer Attributes #1, Vnější průměr: 1010431516015xxxxxxx0; Object Layer Attributes #1, Funkce (venkovní): Ne; Object Layer Attributes #1, Vážená stavební neprůzvučnost: 54; Object Layer Attributes #1, Vlhkostní namáhání oboustranné: Ne; Object Layer Attributes #1, Tloušťka opláštění: 2×12,5; Object Layer Attributes #1, Typ SDK desky: vysokopevnostní+bílá; Object Layer Attributes #1, Způsob opláštění: Oboustranné; Object Layer Attributes #1, Tloušťka izolace (2): 100; Object Layer Attributes #1, Objemová hmotnost izolace: 25; Object Layer Attributes #1, Typ profilu pro SDK: CW 100
VZT | Půdorys 1.NP | Suché stavební práce | 1464SVý1096314064 | m3 | Stěna | NEW | 0.02 | 0.125 | 0.002 | 0.1 | 0.2 | NEMSOK - Object Layer Attributes #1, Označení: VZT; Object Layer Attributes #1, Kód prvku: SN07.03.0001; Object Layer Attributes #1, Podlaží: 1.NP; Object Layer Attributes #1, 2D interakce: yes; Object Layer Attributes #1, Staticky nosná konstrukce: no; Object Layer Attributes #1, Požární odolnost: EI 60; Object Layer Attributes #1, Statická funkce: Ne; Object Layer Attributes #1, Vnější průměr: 1010431516015xxxxxxx0; Object Layer Attributes #1, Funkce (venkovní): Ne; Object Layer Attributes #1, Vážená stavební neprůzvučnost: 54; Object Layer Attributes #1, Vlhkostní namáhání oboustranné: Ne; Object Layer Attributes #1, Tloušťka opláštění: 2×12,5; Object Layer Attributes #1, Typ SDK desky: vysokopevnostní+bílá; Object Layer Attributes #1, Způsob opláštění: Oboustranné; Object Layer Attributes #1, Tloušťka izolace (2): 100; Object Layer Attributes #1, Objemová hmotnost izolace: 25; Object Layer Attributes #1, Typ profilu pro SDK: CW 100
VZT | Půdorys 1.NP | Suché stavební práce | 1464SVý1096314067 | m3 | Stěna | NEW | 0.165 | 0.125 | 0.021 | 0.3 | 0.55 | NEMSOK - Object Layer Attributes #1, Označení: VZT; Object Layer Attributes #1, Kód prvku: SN07.03.0001; Object Layer Attributes #1, Podlaží: 1.NP; Object Layer Attributes #1, 2D interakce: yes; Object Layer Attributes #1, Staticky nosná konstrukce: no; Object Layer Attributes #1, Požární odolnost: EI 60; Object Layer Attributes #1, Statická funkce: Ne; Object Layer Attributes #1, Vnější průměr: 1010431516015xxxxxxx0; Object Layer Attributes #1, Funkce (venkovní): Ne; Object Layer Attributes #1, Vážená stavební neprůzvučnost: 54; Object Layer Attributes #1, Vlhkostní namáhání oboustranné: Ne; Object Layer Attributes #1, Tloušťka opláštění: 2×12,5; Object Layer Attributes #1, Typ SDK desky: vysokopevnostní+bílá; Object Layer Attributes #1, Způsob opláštění: Oboustranné; Object Layer Attributes #1, Tloušťka izolace (2): 100; Object Layer Attributes #1, Objemová hmotnost izolace: 25; Object Layer Attributes #1, Typ profilu pro SDK: CW 100
VZT | Půdorys 1.NP | Suché stavební práce | 1464SVý1096314154 | m3 | Stěna | NEW | 0.02 | 0.125 | 0.002 | 0.1 | 0.2 | NEMSOK - Object Layer Attributes #1, Označení: VZT; Object Layer Attributes #1, Kód prvku: SN07.03.0001; Object Layer Attributes #1, Podlaží: 1.NP; Object Layer Attributes #1, 2D interakce: yes; Object Layer Attributes #1, Staticky nosná konstrukce: no; Object Layer Attributes #1, Požární odolnost: EI 60; Object Layer Attributes #1, Statická funkce: Ne; Object Layer Attributes #1, Vnější průměr: 1010431516015xxxxxxx0; Object Layer Attributes #1, Funkce (venkovní): Ne; Object Layer Attributes #1, Vážená stavební neprůzvučnost: 54; Object Layer Attributes #1, Vlhkostní namáhání oboustranné: Ne; Object Layer Attributes #1, Tloušťka opláštění: 2×12,5; Object Layer Attributes #1, Typ SDK desky: vysokopevnostní+bílá; Object Layer Attributes #1, Způsob opláštění: Oboustranné; Object Layer Attributes #1, Tloušťka izolace (2): 100; Object Layer Attributes #1, Objemová hmotnost izolace: 25; Object Layer Attributes #1, Typ profilu pro SDK: CW 100
VZT | Půdorys 1.NP | Suché stavební práce | 1464SVý1096314436 | m3 | Stěna | NEW | 0.096 | 0.1 | 0.01 | 0.35 | 0.35 | NEMSOK - Object Layer Attributes #1, Označení: VZT; Object Layer Attributes #1, Kód prvku: SN07.03.0001; Object Layer Attributes #1, Podlaží: 1.NP; Object Layer Attributes #1, 2D interakce: yes; Object Layer Attributes #1, Staticky nosná konstrukce: no; Object Layer Attributes #1, Požární odolnost: EI 60; Object Layer Attributes #1, Statická funkce: Ne; Object Layer Attributes #1, Funkce (venkovní): Ne; Object Layer Attributes #1, Vážená stavební neprůzvučnost: 54; Object Layer Attributes #1, Vlhkostní namáhání oboustranné: Ne; Object Layer Attributes #1, Tloušťka opláštění: 2×12,5; Object Layer Attributes #1, Typ SDK desky: vysokopevnostní+bílá; Object Layer Attributes #1, Způsob opláštění: Oboustranné; Object Layer Attributes #1, Tloušťka izolace (2): 100; Object Layer Attributes #1, Objemová hmotnost izolace: 25; Object Layer Attributes #1, Typ profilu pro SDK: CW 100
Dveřní otvor | Půdorys 1.NP | Suché stavební práce | 1464Dve1096314357 | m3 | Stěna | NEW | 2.205 | 0.1 | 0.22 | 2.45 | 0.9 | NEMSOK - Object Layer Attributes #1, Směr otevírání dveří: L; Object Layer Attributes #1, Označení: Dveřní otvor; Object Layer Attributes #1, Kód prvku: SN07.03.0001; Object Layer Attributes #1, Podlaží: 1.NP; Object Layer Attributes #1, 2D interakce: yes; Object Layer Attributes #1, Staticky nosná konstrukce: no; Object Layer Attributes #1, Požární odolnost: EI 60; Object Layer Attributes #1, Statická funkce: Ne; Object Layer Attributes #1, Funkce (venkovní): Ne; Object Layer Attributes #1, Vážená stavební neprůzvučnost: 54; Object Layer Attributes #1, Vlhkostní namáhání oboustranné: Ne; Object Layer Attributes #1, Tloušťka opláštění: 2×12,5; Object Layer Attributes #1, Typ SDK desky: vysokopevnostní+bílá; Object Layer Attributes #1, Způsob opláštění: Oboustranné; Object Layer Attributes #1, Tloušťka izolace (2): 100; Object Layer Attributes #1, Objemová hmotnost izolace: 25; Object Layer Attributes #1, Typ profilu pro SDK: CW 100
ZTI | Půdorys 1.NP | Suché stavební práce | 1464SVý1096314331 | m3 | Stěna | NEW | 0.017 | 0.1 | 0.002 | 0.1 | 0.17 | NEMSOK - Object Layer Attributes #1, Označení: ZTI; Object Layer Attributes #1, Kód prvku: SN07.03.0001; Object Layer Attributes #1, Podlaží: 1.NP; Object Layer Attributes #1, 2D interakce: yes; Object Layer Attributes #1, Staticky nosná konstrukce: no; Object Layer Attributes #1, Požární odolnost: EI 60; Object Layer Attributes #1, Statická funkce: Ne; Object Layer Attributes #1, Vnější průměr: 1010431516015xxxxxxx0; Object Layer Attributes #1, Funkce (venkovní): Ne; Object Layer Attributes #1, Vážená stavební neprůzvučnost: 54; Object Layer Attributes #1, Vlhkostní namáhání oboustranné: Ne; Object Layer Attributes #1, Tloušťka opláštění: 2×12,5; Object Layer Attributes #1, Typ SDK desky: vysokopevnostní+bílá; Object Layer Attributes #1, Způsob opláštění: Oboustranné; Object Layer Attributes #1, Tloušťka izolace (2): 100; Object Layer Attributes #1, Objemová hmotnost izolace: 25; Object Layer Attributes #1, Typ profilu pro SDK: CW 100
VZT | Půdorys 1.NP | Suché stavební práce | 1464SVý1096314338 | m3 | Stěna | NEW | 0.096 | 0.1 | 0.01 | 0.35 | 0.35 | NEMSOK - Object Layer Attributes #1, Označení: VZT; Object Layer Attributes #1, Kód prvku: SN07.03.0001; Object Layer Attributes #1, Podlaží: 1.NP; Object Layer Attributes #1, 2D interakce: yes; Object Layer Attributes #1, Staticky nosná konstrukce: no; Object Layer Attributes #1, Požární odolnost: EI 60; Object Layer Attributes #1, Statická funkce: Ne; Object Layer Attributes #1, Funkce (venkovní): Ne; Object Layer Attributes #1, Vážená stavební neprůzvučnost: 54; Object Layer Attributes #1, Vlhkostní namáhání oboustranné: Ne; Object Layer Attributes #1, Tloušťka opláštění: 2×12,5; Object Layer Attributes #1, Typ SDK desky: vysokopevnostní+bílá; Object Layer Attributes #1, Způsob opláštění: Oboustranné; Object Layer Attributes #1, Tloušťka izolace (2): 100; Object Layer Attributes #1, Objemová hmotnost izolace: 25; Object Layer Attributes #1, Typ profilu pro SDK: CW 100
VZT | Půdorys 1.NP | Suché stavební práce | 1464SVý1096314347 | m3 | Stěna | NEW | 0.096 | 0.1 | 0.01 | 0.35 | 0.35 | NEMSOK - Object Layer Attributes #1, Označení: VZT; Object Layer Attributes #1, Kód prvku: SN07.03.0001; Object Layer Attributes #1, Podlaží: 1.NP; Object Layer Attributes #1, 2D interakce: yes; Object Layer Attributes #1, Staticky nosná konstrukce: no; Object Layer Attributes #1, Požární odolnost: EI 60; Object Layer Attributes #1, Statická funkce: Ne; Object Layer Attributes #1, Funkce (venkovní): Ne; Object Layer Attributes #1, Vážená stavební neprůzvučnost: 54; Object Layer Attributes #1, Vlhkostní namáhání oboustranné: Ne; Object Layer Attributes #1, Tloušťka opláštění: 2×12,5; Object Layer Attributes #1, Typ SDK desky: vysokopevnostní+bílá; Object Layer Attributes #1, Způsob opláštění: Oboustranné; Object Layer Attributes #1, Tloušťka izolace (2): 100; Object Layer Attributes #1, Objemová hmotnost izolace: 25; Object Layer Attributes #1, Typ profilu pro SDK: CW 100
VZT | Půdorys 1.NP | Suché stavební práce | 1464SVý1096314361 | m3 | Stěna | NEW | 0.071 | 0.1 | 0.007 | 0.3 | 0.3 | NEMSOK - Object Layer Attributes #1, Označení: VZT; Object Layer Attributes #1, Kód prvku: SN07.03.0001; Object Layer Attributes #1, Podlaží: 1.NP; Object Layer Attributes #1, 2D interakce: yes; Object Layer Attributes #1, Staticky nosná konstrukce: no; Object Layer Attributes #1, Požární odolnost: EI 60; Object Layer Attributes #1, Statická funkce: Ne; Object Layer Attributes #1, Funkce (venkovní): Ne; Object Layer Attributes #1, Vážená stavební neprůzvučnost: 54; Object Layer Attributes #1, Vlhkostní namáhání oboustranné: Ne; Object Layer Attributes #1, Tloušťka opláštění: 2×12,5; Object Layer Attributes #1, Typ SDK desky: vysokopevnostní+bílá; Object Layer Attributes #1, Způsob opláštění: Oboustranné; Object Layer Attributes #1, Tloušťka izolace (2): 100; Object Layer Attributes #1, Objemová hmotnost izolace: 25; Object Layer Attributes #1, Typ profilu pro SDK: CW 100
ZTI | Půdorys 1.NP | Suché stavební práce | 1464SVý1096314381 | m3 | Stěna | NEW | 0.045 | 0.1 | 0.005 | 0.15 | 0.3 | NEMSOK - Object Layer Attributes #1, Označení: ZTI; Object Layer Attributes #1, Kód prvku: SN07.03.0001; Object Layer Attributes #1, Podlaží: 1.NP; Object Layer Attributes #1, 2D interakce: yes; Object Layer Attributes #1, Staticky nosná konstrukce: no; Object Layer Attributes #1, Požární odolnost: EI 60; Object Layer Attributes #1, Statická funkce: Ne; Object Layer Attributes #1, Vnější průměr: 1010431516015xxxxxxx0; Object Layer Attributes #1, Funkce (venkovní): Ne; Object Layer Attributes #1, Vážená stavební neprůzvučnost: 54; Object Layer Attributes #1, Vlhkostní namáhání oboustranné: Ne; Object Layer Attributes #1, Tloušťka opláštění: 2×12,5; Object Layer Attributes #1, Typ SDK desky: vysokopevnostní+bílá; Object Layer Attributes #1, Způsob opláštění: Oboustranné; Object Layer Attributes #1, Tloušťka izolace (2): 100; Object Layer Attributes #1, Objemová hmotnost izolace: 25; Object Layer Attributes #1, Typ profilu pro SDK: CW 100
Dveřní otvor | Půdorys 1.NP | Suché stavební práce | 1464Dve1096313023 | m3 | Stěna | NEW | 1.96 | 0.125 | 0.245 | 2.45 | 0.8 | NEMSOK - Object Layer Attributes #1, Směr otevírání dveří: P; Object Layer Attributes #1, Označení: Dveřní otvor; Object Layer Attributes #1, Kód prvku: SN07.03.0001; Object Layer Attributes #1, Podlaží: 1.NP; Object Layer Attributes #1, 2D interakce: yes; Object Layer Attributes #1, Staticky nosná konstrukce: no; Object Layer Attributes #1, Požární odolnost: EI 60; Object Layer Attributes #1, Statická funkce: Ne; Object Layer Attributes #1, Funkce (venkovní): Ne; Object Layer Attributes #1, Vážená stavební neprůzvučnost: 54; Object Layer Attributes #1, Vlhkostní namáhání oboustranné: Ne; Object Layer Attributes #1, Tloušťka opláštění: 2×12,5; Object Layer Attributes #1, Typ SDK desky: vysokopevnostní+bílá; Object Layer Attributes #1, Způsob opláštění: Oboustranné; Object Layer Attributes #1, Tloušťka izolace (2): 100; Object Layer Attributes #1, Objemová hmotnost izolace: 25; Object Layer Attributes #1, Typ profilu pro SDK: CW 100
Dveřní otvor | Půdorys 1.NP | Suché stavební práce | 1464Dve1096314413 | m3 | Stěna | NEW | 3.384 | 0.125 | 0.423 | 2.19 | 1.545 | NEMSOK - Object Layer Attributes #1, Směr otevírání dveří: P; Object Layer Attributes #1, Označení: Dveřní otvor; Object Layer Attributes #1, Kód prvku: SN07.03.0001; Object Layer Attributes #1, Podlaží: 1.NP; Object Layer Attributes #1, 2D interakce: yes; Object Layer Attributes #1, Staticky nosná konstrukce: no; Object Layer Attributes #1, Požární odolnost: EI 60; Object Layer Attributes #1, Statická funkce: Ne; Object Layer Attributes #1, Funkce (venkovní): Ne; Object Layer Attributes #1, Vážená stavební neprůzvučnost: 54; Object Layer Attributes #1, Vlhkostní namáhání oboustranné: Ne; Object Layer Attributes #1, Tloušťka opláštění: 2×12,5; Object Layer Attributes #1, Typ SDK desky: vysokopevnostní+bílá; Object Layer Attributes #1, Způsob opláštění: Oboustranné; Object Layer Attributes #1, Tloušťka izolace (2): 100; Object Layer Attributes #1, Objemová hmotnost izolace: 25; Object Layer Attributes #1, Typ profilu pro SDK: CW 100
ZTI | Půdorys 1.NP | Suché stavební práce | 1464SVý1096314390 | m3 | Stěna | NEW | 0.031 | 0.125 | 0.004 | 0.2 | 0.2 | NEMSOK - Object Layer Attributes #1, Označení: ZTI; Object Layer Attributes #1, Kód prvku: SN07.03.0001; Object Layer Attributes #1, Podlaží: 1.NP; Object Layer Attributes #1, 2D interakce: yes; Object Layer Attributes #1, Staticky nosná konstrukce: no; Object Layer Attributes #1, Požární odolnost: EI 60; Object Layer Attributes #1, Statická funkce: Ne; Object Layer Attributes #1, Funkce (venkovní): Ne; Object Layer Attributes #1, Vážená stavební neprůzvučnost: 54; Object Layer Attributes #1, Vlhkostní namáhání oboustranné: Ne; Object Layer Attributes #1, Tloušťka opláštění: 2×12,5; Object Layer Attributes #1, Typ SDK desky: vysokopevnostní+bílá; Object Layer Attributes #1, Způsob opláštění: Oboustranné; Object Layer Attributes #1, Tloušťka izolace (2): 100; Object Layer Attributes #1, Objemová hmotnost izolace: 25; Object Layer Attributes #1, Typ profilu pro SDK: CW 100
VZT | Půdorys 1.NP | Suché stavební práce | 1464SVý1096314427 | m3 | Stěna | NEW | 0.049 | 0.125 | 0.006 | 0.25 | 0.25 | NEMSOK - Object Layer Attributes #1, Označení: VZT; Object Layer Attributes #1, Kód prvku: SN07.03.0001; Object Layer Attributes #1, Podlaží: 1.NP; Object Layer Attributes #1, 2D interakce: yes; Object Layer Attributes #1, Staticky nosná konstrukce: no; Object Layer Attributes #1, Požární odolnost: EI 60; Object Layer Attributes #1, Statická funkce: Ne; Object Layer Attributes #1, Funkce (venkovní): Ne; Object Layer Attributes #1, Vážená stavební neprůzvučnost: 54; Object Layer Attributes #1, Vlhkostní namáhání oboustranné: Ne; Object Layer Attributes #1, Tloušťka opláštění: 2×12,5; Object Layer Attributes #1, Typ SDK desky: vysokopevnostní+bílá; Object Layer Attributes #1, Způsob opláštění: Oboustranné; Object Layer Attributes #1, Tloušťka izolace (2): 100; Object Layer Attributes #1, Objemová hmotnost izolace: 25; Object Layer Attributes #1, Typ profilu pro SDK: CW 100
Stěnová nika | Půdorys 1.NP | Suché stavební práce | 1464SNi1096316145 | m3 | Stěna | NEW | 2.01 | 0.1 | 0.201 | 3.35 | 0.6 | NEMSOK - Object Layer Attributes #1, Označení: Stěnová nika; Object Layer Attributes #1, Kód prvku: SN07.03.0001; Object Layer Attributes #1, Podlaží: 1.NP; Object Layer Attributes #1, 2D interakce: yes; Object Layer Attributes #1, Staticky nosná konstrukce: no; Object Layer Attributes #1, Požární odolnost: EI 60; Object Layer Attributes #1, Statická funkce: Ne; Object Layer Attributes #1, Funkce (venkovní): Ne; Object Layer Attributes #1, Vážená stavební neprůzvučnost: 54; Object Layer Attributes #1, Vlhkostní namáhání oboustranné: Ne; Object Layer Attributes #1, Tloušťka opláštění: 2×12,5; Object Layer Attributes #1, Typ SDK desky: vysokopevnostní+bílá; Object Layer Attributes #1, Způsob opláštění: Oboustranné; Object Layer Attributes #1, Tloušťka izolace (2): 100; Object Layer Attributes #1, Objemová hmotnost izolace: 25; Object Layer Attributes #1, Typ profilu pro SDK: CW 100
VZT | Půdorys 1.NP | Suché stavební práce | 1464SVý1096313739 | m3 | Stěna | NEW | 0.061 | 0.125 | 0.008 | 0.28 | 0.28 | NEMSOK - Object Layer Attributes #1, Označení: VZT; Object Layer Attributes #1, Kód prvku: SN07.03.0001; Object Layer Attributes #1, Podlaží: 1.NP; Object Layer Attributes #1, 2D interakce: yes; Object Layer Attributes #1, Staticky nosná konstrukce: no; Object Layer Attributes #1, Požární odolnost: EI 60; Object Layer Attributes #1, Statická funkce: Ne; Object Layer Attributes #1, Funkce (venkovní): Ne; Object Layer Attributes #1, Vážená stavební neprůzvučnost: 54; Object Layer Attributes #1, Vlhkostní namáhání oboustranné: Ne; Object Layer Attributes #1, Tloušťka opláštění: 2×12,5; Object Layer Attributes #1, Typ SDK desky: vysokopevnostní+bílá; Object Layer Attributes #1, Způsob opláštění: Oboustranné; Object Layer Attributes #1, Tloušťka izolace (2): 100; Object Layer Attributes #1, Objemová hmotnost izolace: 25; Object Layer Attributes #1, Typ profilu pro SDK: CW 100
ZTI | Půdorys 1.NP | Suché stavební práce | 1464SVý1096313745 | m3 | Stěna | NEW | 0.019 | 0.125 | 0.002 | 0.11 | 0.175 | NEMSOK - Object Layer Attributes #1, Označení: ZTI; Object Layer Attributes #1, Kód prvku: SN07.03.0001; Object Layer Attributes #1, Podlaží: 1.NP; Object Layer Attributes #1, 2D interakce: yes; Object Layer Attributes #1, Staticky nosná konstrukce: no; Object Layer Attributes #1, Požární odolnost: EI 60; Object Layer Attributes #1, Statická funkce: Ne; Object Layer Attributes #1, Vnější průměr: 1010431516015xxxxxxx0; Object Layer Attributes #1, Funkce (venkovní): Ne; Object Layer Attributes #1, Vážená stavební neprůzvučnost: 54; Object Layer Attributes #1, Vlhkostní namáhání oboustranné: Ne; Object Layer Attributes #1, Tloušťka opláštění: 2×12,5; Object Layer Attributes #1, Typ SDK desky: vysokopevnostní+bílá; Object Layer Attributes #1, Způsob opláštění: Oboustranné; Object Layer Attributes #1, Tloušťka izolace (2): 100; Object Layer Attributes #1, Objemová hmotnost izolace: 25; Object Layer Attributes #1, Typ profilu pro SDK: CW 100
Dveřní otvor | Půdorys 1.NP | Suché stavební práce | 1464Dve1096313799 | m3 | Stěna | NEW | 3.769 | 0.125 | 0.471 | 2.16 | 1.745 | NEMSOK - Object Layer Attributes #1, Směr otevírání dveří: P; Object Layer Attributes #1, Označení: Dveřní otvor; Object Layer Attributes #1, Kód prvku: SN07.03.0001; Object Layer Attributes #1, Podlaží: 1.NP; Object Layer Attributes #1, 2D interakce: yes; Object Layer Attributes #1, Staticky nosná konstrukce: no; Object Layer Attributes #1, Požární odolnost: EI 60; Object Layer Attributes #1, Statická funkce: Ne; Object Layer Attributes #1, Funkce (venkovní): Ne; Object Layer Attributes #1, Vážená stavební neprůzvučnost: 54; Object Layer Attributes #1, Vlhkostní namáhání oboustranné: Ne; Object Layer Attributes #1, Tloušťka opláštění: 2×12,5; Object Layer Attributes #1, Typ SDK desky: vysokopevnostní+bílá; Object Layer Attributes #1, Způsob opláštění: Oboustranné; Object Layer Attributes #1, Tloušťka izolace (2): 100; Object Layer Attributes #1, Objemová hmotnost izolace: 25; Object Layer Attributes #1, Typ profilu pro SDK: CW 100
VZT | Půdorys 1.NP | Suché stavební práce | 1464SVý1096313813 | m3 | Stěna | NEW | 0.053 | 0.125 | 0.007 | 0.26 | 0.26 | NEMSOK - Object Layer Attributes #1, Označení: VZT; Object Layer Attributes #1, Kód prvku: SN07.03.0001; Object Layer Attributes #1, Podlaží: 1.NP; Object Layer Attributes #1, 2D interakce: yes; Object Layer Attributes #1, Staticky nosná konstrukce: no; Object Layer Attributes #1, Požární odolnost: EI 60; Object Layer Attributes #1, Statická funkce: Ne; Object Layer Attributes #1, Funkce (venkovní): Ne; Object Layer Attributes #1, Vážená stavební neprůzvučnost: 54; Object Layer Attributes #1, Vlhkostní namáhání oboustranné: Ne; Object Layer Attributes #1, Tloušťka opláštění: 2×12,5; Object Layer Attributes #1, Typ SDK desky: vysokopevnostní+bílá; Object Layer Attributes #1, Způsob opláštění: Oboustranné; Object Layer Attributes #1, Tloušťka izolace (2): 100; Object Layer Attributes #1, Objemová hmotnost izolace: 25; Object Layer Attributes #1, Typ profilu pro SDK: CW 100
Dveřní otvor | Půdorys 1.NP | Suché stavební práce | 1464Dve1096313076 | m3 | Stěna | NEW | 4.201 | 0.125 | 0.525 | 2.16 | 1.945 | NEMSOK - Object Layer Attributes #1, Směr otevírání dveří: L; Object Layer Attributes #1, Označení: Dveřní otvor; Object Layer Attributes #1, Kód prvku: SN07.03.0001; Object Layer Attributes #1, Podlaží: 1.NP; Object Layer Attributes #1, 2D interakce: yes; Object Layer Attributes #1, Staticky nosná konstrukce: no; Object Layer Attributes #1, Požární odolnost: EI 60; Object Layer Attributes #1, Statická funkce: Ne; Object Layer Attributes #1, Funkce (venkovní): Ne; Object Layer Attributes #1, Vážená stavební neprůzvučnost: 54; Object Layer Attributes #1, Vlhkostní namáhání oboustranné: Ne; Object Layer Attributes #1, Tloušťka opláštění: 2×12,5; Object Layer Attributes #1, Typ SDK desky: vysokopevnostní+bílá; Object Layer Attributes #1, Způsob opláštění: Oboustranné; Object Layer Attributes #1, Tloušťka izolace (2): 100; Object Layer Attributes #1, Objemová hmotnost izolace: 25; Object Layer Attributes #1, Typ profilu pro SDK: CW 100
Dveřní otvor | Půdorys 1.NP | Suché stavební práce | 1464Dve1096313662 | m3 | Stěna | NEW | 4.201 | 0.125 | 0.525 | 2.16 | 1.945 | NEMSOK - Object Layer Attributes #1, Směr otevírání dveří: L; Object Layer Attributes #1, Označení: Dveřní otvor; Object Layer Attributes #1, Kód prvku: SN07.03.0001; Object Layer Attributes #1, Podlaží: 1.NP; Object Layer Attributes #1, 2D interakce: yes; Object Layer Attributes #1, Staticky nosná konstrukce: no; Object Layer Attributes #1, Požární odolnost: EI 60; Object Layer Attributes #1, Statická funkce: Ne; Object Layer Attributes #1, Funkce (venkovní): Ne; Object Layer Attributes #1, Vážená stavební neprůzvučnost: 54; Object Layer Attributes #1, Vlhkostní namáhání oboustranné: Ne; Object Layer Attributes #1, Tloušťka opláštění: 2×12,5; Object Layer Attributes #1, Typ SDK desky: vysokopevnostní+bílá; Object Layer Attributes #1, Způsob opláštění: Oboustranné; Object Layer Attributes #1, Tloušťka izolace (2): 100; Object Layer Attributes #1, Objemová hmotnost izolace: 25; Object Layer Attributes #1, Typ profilu pro SDK: CW 100
Dveřní otvor | Půdorys 1.NP | Suché stavební práce | 1464Dve1096313679 | m3 | Stěna | NEW | 4.201 | 0.125 | 0.525 | 2.16 | 1.945 | NEMSOK - Object Layer Attributes #1, Směr otevírání dveří: P; Object Layer Attributes #1, Označení: Dveřní otvor; Object Layer Attributes #1, Kód prvku: SN07.03.0001; Object Layer Attributes #1, Podlaží: 1.NP; Object Layer Attributes #1, 2D interakce: yes; Object Layer Attributes #1, Staticky nosná konstrukce: no; Object Layer Attributes #1, Požární odolnost: EI 60; Object Layer Attributes #1, Statická funkce: Ne; Object Layer Attributes #1, Funkce (venkovní): Ne; Object Layer Attributes #1, Vážená stavební neprůzvučnost: 54; Object Layer Attributes #1, Vlhkostní namáhání oboustranné: Ne; Object Layer Attributes #1, Tloušťka opláštění: 2×12,5; Object Layer Attributes #1, Typ SDK desky: vysokopevnostní+bílá; Object Layer Attributes #1, Způsob opláštění: Oboustranné; Object Layer Attributes #1, Tloušťka izolace (2): 100; Object Layer Attributes #1, Objemová hmotnost izolace: 25; Object Layer Attributes #1, Typ profilu pro SDK: CW 100
ZTI | Půdorys 1.NP | Suché stavební práce | 1464SVý1096313666 | m3 | Stěna | NEW | 0.019 | 0.125 | 0.002 | 0.11 | 0.175 | NEMSOK - Object Layer Attributes #1, Označení: ZTI; Object Layer Attributes #1, Kód prvku: SN07.03.0001; Object Layer Attributes #1, Podlaží: 1.NP; Object Layer Attributes #1, 2D interakce: yes; Object Layer Attributes #1, Staticky nosná konstrukce: no; Object Layer Attributes #1, Požární odolnost: EI 60; Object Layer Attributes #1, Statická funkce: Ne; Object Layer Attributes #1, Vnější průměr: 1010431516015xxxxxxx0; Object Layer Attributes #1, Funkce (venkovní): Ne; Object Layer Attributes #1, Vážená stavební neprůzvučnost: 54; Object Layer Attributes #1, Vlhkostní namáhání oboustranné: Ne; Object Layer Attributes #1, Tloušťka opláštění: 2×12,5; Object Layer Attributes #1, Typ SDK desky: vysokopevnostní+bílá; Object Layer Attributes #1, Způsob opláštění: Oboustranné; Object Layer Attributes #1, Tloušťka izolace (2): 100; Object Layer Attributes #1, Objemová hmotnost izolace: 25; Object Layer Attributes #1, Typ profilu pro SDK: CW 100
VZT | Půdorys 1.NP | Suché stavební práce | 1464SVý1096313703 | m3 | Stěna | NEW | 0.049 | 0.125 | 0.006 | 0.25 | 0.25 | NEMSOK - Object Layer Attributes #1, Označení: VZT; Object Layer Attributes #1, Kód prvku: SN07.03.0001; Object Layer Attributes #1, Podlaží: 1.NP; Object Layer Attributes #1, 2D interakce: yes; Object Layer Attributes #1, Staticky nosná konstrukce: no; Object Layer Attributes #1, Požární odolnost: EI 60; Object Layer Attributes #1, Statická funkce: Ne; Object Layer Attributes #1, Funkce (venkovní): Ne; Object Layer Attributes #1, Vážená stavební neprůzvučnost: 54; Object Layer Attributes #1, Vlhkostní namáhání oboustranné: Ne; Object Layer Attributes #1, Tloušťka opláštění: 2×12,5; Object Layer Attributes #1, Typ SDK desky: vysokopevnostní+bílá; Object Layer Attributes #1, Způsob opláštění: Oboustranné; Object Layer Attributes #1, Tloušťka izolace (2): 100; Object Layer Attributes #1, Objemová hmotnost izolace: 25; Object Layer Attributes #1, Typ profilu pro SDK: CW 100
VZT | Půdorys 1.NP | Suché stavební práce | 1464SVý1096313637 | m3 | Stěna | NEW | 0.031 | 0.1 | 0.003 | 0.2 | 0.2 | NEMSOK - Object Layer Attributes #1, Označení: VZT; Object Layer Attributes #1, Kód prvku: SN07.03.0001; Object Layer Attributes #1, Podlaží: 1.NP; Object Layer Attributes #1, 2D interakce: yes; Object Layer Attributes #1, Staticky nosná konstrukce: no; Object Layer Attributes #1, Požární odolnost: EI 60; Object Layer Attributes #1, Statická funkce: Ne; Object Layer Attributes #1, Funkce (venkovní): Ne; Object Layer Attributes #1, Vážená stavební neprůzvučnost: 54; Object Layer Attributes #1, Vlhkostní namáhání oboustranné: Ne; Object Layer Attributes #1, Tloušťka opláštění: 2×12,5; Object Layer Attributes #1, Typ SDK desky: vysokopevnostní+bílá; Object Layer Attributes #1, Způsob opláštění: Oboustranné; Object Layer Attributes #1, Tloušťka izolace (2): 100; Object Layer Attributes #1, Objemová hmotnost izolace: 25; Object Layer Attributes #1, Typ profilu pro SDK: CW 100
VZT | Půdorys 1.NP | Suché stavební práce | 1464SVý1096313645 | m3 | Stěna | NEW | 0.031 | 0.1 | 0.003 | 0.2 | 0.2 | NEMSOK - Object Layer Attributes #1, Označení: VZT; Object Layer Attributes #1, Kód prvku: SN07.03.0001; Object Layer Attributes #1, Podlaží: 1.NP; Object Layer Attributes #1, 2D interakce: yes; Object Layer Attributes #1, Staticky nosná konstrukce: no; Object Layer Attributes #1, Požární odolnost: EI 60; Object Layer Attributes #1, Statická funkce: Ne; Object Layer Attributes #1, Funkce (venkovní): Ne; Object Layer Attributes #1, Vážená stavební neprůzvučnost: 54; Object Layer Attributes #1, Vlhkostní namáhání oboustranné: Ne; Object Layer Attributes #1, Tloušťka opláštění: 2×12,5; Object Layer Attributes #1, Typ SDK desky: vysokopevnostní+bílá; Object Layer Attributes #1, Způsob opláštění: Oboustranné; Object Layer Attributes #1, Tloušťka izolace (2): 100; Object Layer Attributes #1, Objemová hmotnost izolace: 25; Object Layer Attributes #1, Typ profilu pro SDK: CW 100
Dveřní otvor | Půdorys 1.NP | Suché stavební práce | 1464Dve1096314555 | m3 | Stěna | NEW | 2.025 | 0.125 | 0.253 | 2.25 | 0.9 | NEMSOK - Object Layer Attributes #1, Směr otevírání dveří: L; Object Layer Attributes #1, Označení: Dveřní otvor; Object Layer Attributes #1, Kód prvku: SN07.03.0001; Object Layer Attributes #1, Podlaží: 1.NP; Object Layer Attributes #1, 2D interakce: yes; Object Layer Attributes #1, Staticky nosná konstrukce: no; Object Layer Attributes #1, Požární odolnost: EI 60; Object Layer Attributes #1, Statická funkce: Ne; Object Layer Attributes #1, Funkce (venkovní): Ne; Object Layer Attributes #1, Vážená stavební neprůzvučnost: 54; Object Layer Attributes #1, Vlhkostní namáhání oboustranné: Ne; Object Layer Attributes #1, Tloušťka opláštění: 2×12,5; Object Layer Attributes #1, Typ SDK desky: vysokopevnostní+bílá; Object Layer Attributes #1, Způsob opláštění: Oboustranné; Object Layer Attributes #1, Tloušťka izolace (2): 100; Object Layer Attributes #1, Objemová hmotnost izolace: 25; Object Layer Attributes #1, Typ profilu pro SDK: CW 100
Dveřní otvor | Půdorys 1.NP | Suché stavební práce | 1464Dve1096314597 | m3 | Stěna | NEW | 2.025 | 0.125 | 0.253 | 2.25 | 0.9 | NEMSOK - Object Layer Attributes #1, Směr otevírání dveří: P; Object Layer Attributes #1, Označení: Dveřní otvor; Object Layer Attributes #1, Kód prvku: SN07.03.0001; Object Layer Attributes #1, Podlaží: 1.NP; Object Layer Attributes #1, 2D interakce: yes; Object Layer Attributes #1, Staticky nosná konstrukce: no; Object Layer Attributes #1, Požární odolnost: EI 60; Object Layer Attributes #1, Statická funkce: Ne; Object Layer Attributes #1, Funkce (venkovní): Ne; Object Layer Attributes #1, Vážená stavební neprůzvučnost: 54; Object Layer Attributes #1, Vlhkostní namáhání oboustranné: Ne; Object Layer Attributes #1, Tloušťka opláštění: 2×12,5; Object Layer Attributes #1, Typ SDK desky: vysokopevnostní+bílá; Object Layer Attributes #1, Způsob opláštění: Oboustranné; Object Layer Attributes #1, Tloušťka izolace (2): 100; Object Layer Attributes #1, Objemová hmotnost izolace: 25; Object Layer Attributes #1, Typ profilu pro SDK: CW 100
ZTI | Půdorys 1.NP | Suché stavební práce | 1464SVý1096314528 | m3 | Stěna | NEW | 0.019 | 0.125 | 0.002 | 0.11 | 0.175 | NEMSOK - Object Layer Attributes #1, Označení: ZTI; Object Layer Attributes #1, Kód prvku: SN07.03.0001; Object Layer Attributes #1, Podlaží: 1.NP; Object Layer Attributes #1, 2D interakce: yes; Object Layer Attributes #1, Staticky nosná konstrukce: no; Object Layer Attributes #1, Požární odolnost: EI 60; Object Layer Attributes #1, Statická funkce: Ne; Object Layer Attributes #1, Vnější průměr: 1010431516015xxxxxxx0; Object Layer Attributes #1, Funkce (venkovní): Ne; Object Layer Attributes #1, Vážená stavební neprůzvučnost: 54; Object Layer Attributes #1, Vlhkostní namáhání oboustranné: Ne; Object Layer Attributes #1, Tloušťka opláštění: 2×12,5; Object Layer Attributes #1, Typ SDK desky: vysokopevnostní+bílá; Object Layer Attributes #1, Způsob opláštění: Oboustranné; Object Layer Attributes #1, Tloušťka izolace (2): 100; Object Layer Attributes #1, Objemová hmotnost izolace: 25; Object Layer Attributes #1, Typ profilu pro SDK: CW 100
VZT | Půdorys 1.NP | Suché stavební práce | 1464SVý1096314536 | m3 | Stěna | NEW | 0.049 | 0.125 | 0.006 | 0.25 | 0.25 | NEMSOK - Object Layer Attributes #1, Označení: VZT; Object Layer Attributes #1, Kód prvku: SN07.03.0001; Object Layer Attributes #1, Podlaží: 1.NP; Object Layer Attributes #1, 2D interakce: yes; Object Layer Attributes #1, Staticky nosná konstrukce: no; Object Layer Attributes #1, Požární odolnost: EI 60; Object Layer Attributes #1, Statická funkce: Ne; Object Layer Attributes #1, Funkce (venkovní): Ne; Object Layer Attributes #1, Vážená stavební neprůzvučnost: 54; Object Layer Attributes #1, Vlhkostní namáhání oboustranné: Ne; Object Layer Attributes #1, Tloušťka opláštění: 2×12,5; Object Layer Attributes #1, Typ SDK desky: vysokopevnostní+bílá; Object Layer Attributes #1, Způsob opláštění: Oboustranné; Object Layer Attributes #1, Tloušťka izolace (2): 100; Object Layer Attributes #1, Objemová hmotnost izolace: 25; Object Layer Attributes #1, Typ profilu pro SDK: CW 100
VZT | Půdorys 1.NP | Suché stavební práce | 1464SVý1096314552 | m3 | Stěna | NEW | 0.049 | 0.125 | 0.006 | 0.25 | 0.25 | NEMSOK - Object Layer Attributes #1, Označení: VZT; Object Layer Attributes #1, Kód prvku: SN07.03.0001; Object Layer Attributes #1, Podlaží: 1.NP; Object Layer Attributes #1, 2D interakce: yes; Object Layer Attributes #1, Staticky nosná konstrukce: no; Object Layer Attributes #1, Požární odolnost: EI 60; Object Layer Attributes #1, Statická funkce: Ne; Object Layer Attributes #1, Funkce (venkovní): Ne; Object Layer Attributes #1, Vážená stavební neprůzvučnost: 54; Object Layer Attributes #1, Vlhkostní namáhání oboustranné: Ne; Object Layer Attributes #1, Tloušťka opláštění: 2×12,5; Object Layer Attributes #1, Typ SDK desky: vysokopevnostní+bílá; Object Layer Attributes #1, Způsob opláštění: Oboustranné; Object Layer Attributes #1, Tloušťka izolace (2): 100; Object Layer Attributes #1, Objemová hmotnost izolace: 25; Object Layer Attributes #1, Typ profilu pro SDK: CW 100
ZTI | Půdorys 1.NP | Suché stavební práce | 1464SVý1096314594 | m3 | Stěna | NEW | 0.031 | 0.125 | 0.004 | 0.2 | 0.2 | NEMSOK - Object Layer Attributes #1, Označení: ZTI; Object Layer Attributes #1, Kód prvku: SN07.03.0001; Object Layer Attributes #1, Podlaží: 1.NP; Object Layer Attributes #1, 2D interakce: yes; Object Layer Attributes #1, Staticky nosná konstrukce: no; Object Layer Attributes #1, Požární odolnost: EI 60; Object Layer Attributes #1, Statická funkce: Ne; Object Layer Attributes #1, Funkce (venkovní): Ne; Object Layer Attributes #1, Vážená stavební neprůzvučnost: 54; Object Layer Attributes #1, Vlhkostní namáhání oboustranné: Ne; Object Layer Attributes #1, Tloušťka opláštění: 2×12,5; Object Layer Attributes #1, Typ SDK desky: vysokopevnostní+bílá; Object Layer Attributes #1, Způsob opláštění: Oboustranné; Object Layer Attributes #1, Tloušťka izolace (2): 100; Object Layer Attributes #1, Objemová hmotnost izolace: 25; Object Layer Attributes #1, Typ profilu pro SDK: CW 100
Dveřní otvor | Půdorys 1.NP | Suché stavební práce | 1464Dve1096313170 | m3 | Stěna | NEW | 1.96 | 0.125 | 0.245 | 2.45 | 0.8 | NEMSOK - Object Layer Attributes #1, Směr otevírání dveří: P; Object Layer Attributes #1, Označení: Dveřní otvor; Object Layer Attributes #1, Kód prvku: SN07.03.0001; Object Layer Attributes #1, Podlaží: 1.NP; Object Layer Attributes #1, 2D interakce: yes; Object Layer Attributes #1, Staticky nosná konstrukce: no; Object Layer Attributes #1, Požární odolnost: EI 60; Object Layer Attributes #1, Statická funkce: Ne; Object Layer Attributes #1, Funkce (venkovní): Ne; Object Layer Attributes #1, Vážená stavební neprůzvučnost: 54; Object Layer Attributes #1, Vlhkostní namáhání oboustranné: Ne; Object Layer Attributes #1, Tloušťka opláštění: 2×12,5; Object Layer Attributes #1, Typ SDK desky: vysokopevnostní+bílá; Object Layer Attributes #1, Způsob opláštění: Oboustranné; Object Layer Attributes #1, Tloušťka izolace (2): 100; Object Layer Attributes #1, Objemová hmotnost izolace: 25; Object Layer Attributes #1, Typ profilu pro SDK: CW 100
Dveřní otvor | Půdorys 1.NP | Suché stavební práce | 1464Dve1096314447 | m3 | Stěna | NEW | 1.96 | 0.125 | 0.245 | 2.45 | 0.8 | NEMSOK - Object Layer Attributes #1, Směr otevírání dveří: P; Object Layer Attributes #1, Označení: Dveřní otvor; Object Layer Attributes #1, Kód prvku: SN07.03.0001; Object Layer Attributes #1, Podlaží: 1.NP; Object Layer Attributes #1, 2D interakce: yes; Object Layer Attributes #1, Staticky nosná konstrukce: no; Object Layer Attributes #1, Požární odolnost: EI 60; Object Layer Attributes #1, Statická funkce: Ne; Object Layer Attributes #1, Funkce (venkovní): Ne; Object Layer Attributes #1, Vážená stavební neprůzvučnost: 54; Object Layer Attributes #1, Vlhkostní namáhání oboustranné: Ne; Object Layer Attributes #1, Tloušťka opláštění: 2×12,5; Object Layer Attributes #1, Typ SDK desky: vysokopevnostní+bílá; Object Layer Attributes #1, Způsob opláštění: Oboustranné; Object Layer Attributes #1, Tloušťka izolace (2): 100; Object Layer Attributes #1, Objemová hmotnost izolace: 25; Object Layer Attributes #1, Typ profilu pro SDK: CW 100
VZT | Půdorys 1.NP | Suché stavební práce | 1464SVý1096314458 | m3 | Stěna | NEW | 0.049 | 0.125 | 0.006 | 0.25 | 0.25 | NEMSOK - Object Layer Attributes #1, Označení: VZT; Object Layer Attributes #1, Kód prvku: SN07.03.0001; Object Layer Attributes #1, Podlaží: 1.NP; Object Layer Attributes #1, 2D interakce: yes; Object Layer Attributes #1, Staticky nosná konstrukce: no; Object Layer Attributes #1, Požární odolnost: EI 60; Object Layer Attributes #1, Statická funkce: Ne; Object Layer Attributes #1, Funkce (venkovní): Ne; Object Layer Attributes #1, Vážená stavební neprůzvučnost: 54; Object Layer Attributes #1, Vlhkostní namáhání oboustranné: Ne; Object Layer Attributes #1, Tloušťka opláštění: 2×12,5; Object Layer Attributes #1, Typ SDK desky: vysokopevnostní+bílá; Object Layer Attributes #1, Způsob opláštění: Oboustranné; Object Layer Attributes #1, Tloušťka izolace (2): 100; Object Layer Attributes #1, Objemová hmotnost izolace: 25; Object Layer Attributes #1, Typ profilu pro SDK: CW 100
VZT | Půdorys 1.NP | Suché stavební práce | 1464SVý1096314491 | m3 | Stěna | NEW | 0.096 | 0.15 | 0.014 | 0.35 | 0.35 | NEMSOK - Object Layer Attributes #1, Označení: VZT; Object Layer Attributes #1, Kód prvku: SN07.03.0001; Object Layer Attributes #1, Podlaží: 1.NP; Object Layer Attributes #1, 2D interakce: yes; Object Layer Attributes #1, Staticky nosná konstrukce: no; Object Layer Attributes #1, Požární odolnost: EI 60; Object Layer Attributes #1, Statická funkce: Ne; Object Layer Attributes #1, Funkce (venkovní): Ne; Object Layer Attributes #1, Vážená stavební neprůzvučnost: 54; Object Layer Attributes #1, Vlhkostní namáhání oboustranné: Ne; Object Layer Attributes #1, Tloušťka opláštění: 2×12,5; Object Layer Attributes #1, Typ SDK desky: vysokopevnostní+bílá; Object Layer Attributes #1, Způsob opláštění: Oboustranné; Object Layer Attributes #1, Tloušťka izolace (2): 100; Object Layer Attributes #1, Objemová hmotnost izolace: 25; Object Layer Attributes #1, Typ profilu pro SDK: CW 100
VZT | Půdorys 1.NP | Suché stavební práce | 1464SVý1096314468 | m3 | Stěna | NEW | 0.049 | 0.1 | 0.005 | 0.25 | 0.25 | NEMSOK - Object Layer Attributes #1, Označení: VZT; Object Layer Attributes #1, Kód prvku: SN07.03.0001; Object Layer Attributes #1, Podlaží: 1.NP; Object Layer Attributes #1, 2D interakce: yes; Object Layer Attributes #1, Staticky nosná konstrukce: no; Object Layer Attributes #1, Požární odolnost: EI 60; Object Layer Attributes #1, Statická funkce: Ne; Object Layer Attributes #1, Funkce (venkovní): Ne; Object Layer Attributes #1, Vážená stavební neprůzvučnost: 54; Object Layer Attributes #1, Vlhkostní namáhání oboustranné: Ne; Object Layer Attributes #1, Tloušťka opláštění: 2×12,5; Object Layer Attributes #1, Typ SDK desky: vysokopevnostní+bílá; Object Layer Attributes #1, Způsob opláštění: Oboustranné; Object Layer Attributes #1, Tloušťka izolace (2): 100; Object Layer Attributes #1, Objemová hmotnost izolace: 25; Object Layer Attributes #1, Typ profilu pro SDK: CW 100
CHL | Půdorys 1.NP | Suché stavební práce | 1464SVý1096313758 | m3 | Stěna | NEW | 0.015 | 0.125 | 0.002 | 0.15 | 0.1 | NEMSOK - Object Layer Attributes #1, Označení: CHL; Object Layer Attributes #1, Kód prvku: SN07.03.0001; Object Layer Attributes #1, Podlaží: 1.NP; Object Layer Attributes #1, 2D interakce: yes; Object Layer Attributes #1, Staticky nosná konstrukce: no; Object Layer Attributes #1, Požární odolnost: EI 60; Object Layer Attributes #1, Statická funkce: Ne; Object Layer Attributes #1, Vnější průměr: 1010431516015xxxxxxx0; Object Layer Attributes #1, Funkce (venkovní): Ne; Object Layer Attributes #1, Vážená stavební neprůzvučnost: 54; Object Layer Attributes #1, Vlhkostní namáhání oboustranné: Ne; Object Layer Attributes #1, Tloušťka opláštění: 2×12,5; Object Layer Attributes #1, Typ SDK desky: vysokopevnostní+bílá; Object Layer Attributes #1, Způsob opláštění: Oboustranné; Object Layer Attributes #1, Tloušťka izolace (2): 100; Object Layer Attributes #1, Objemová hmotnost izolace: 25; Object Layer Attributes #1, Typ profilu pro SDK: CW 100
VZT | Půdorys 1.NP | Suché stavební práce | 1464SVý1096313770 | m3 | Stěna | NEW | 0.125 | 0.125 | 0.016 | 0.3 | 0.415 | NEMSOK - Object Layer Attributes #1, Označení: VZT; Object Layer Attributes #1, Kód prvku: SN07.03.0001; Object Layer Attributes #1, Podlaží: 1.NP; Object Layer Attributes #1, 2D interakce: yes; Object Layer Attributes #1, Staticky nosná konstrukce: no; Object Layer Attributes #1, Požární odolnost: EI 60; Object Layer Attributes #1, Statická funkce: Ne; Object Layer Attributes #1, Vnější průměr: 1010431516015xxxxxxx0; Object Layer Attributes #1, Funkce (venkovní): Ne; Object Layer Attributes #1, Vážená stavební neprůzvučnost: 54; Object Layer Attributes #1, Vlhkostní namáhání oboustranné: Ne; Object Layer Attributes #1, Tloušťka opláštění: 2×12,5; Object Layer Attributes #1, Typ SDK desky: vysokopevnostní+bílá; Object Layer Attributes #1, Způsob opláštění: Oboustranné; Object Layer Attributes #1, Tloušťka izolace (2): 100; Object Layer Attributes #1, Objemová hmotnost izolace: 25; Object Layer Attributes #1, Typ profilu pro SDK: CW 100
VZT | Půdorys 1.NP | Suché stavební práce | 1464SVý1096314149 | m3 | Stěna | NEW | 0.165 | 0.125 | 0.021 | 0.3 | 0.55 | NEMSOK - Object Layer Attributes #1, Označení: VZT; Object Layer Attributes #1, Kód prvku: SN07.03.0001; Object Layer Attributes #1, Podlaží: 1.NP; Object Layer Attributes #1, 2D interakce: yes; Object Layer Attributes #1, Staticky nosná konstrukce: no; Object Layer Attributes #1, Požární odolnost: EI 60; Object Layer Attributes #1, Statická funkce: Ne; Object Layer Attributes #1, Vnější průměr: 1010431516015xxxxxxx0; Object Layer Attributes #1, Funkce (venkovní): Ne; Object Layer Attributes #1, Vážená stavební neprůzvučnost: 54; Object Layer Attributes #1, Vlhkostní namáhání oboustranné: Ne; Object Layer Attributes #1, Tloušťka opláštění: 2×12,5; Object Layer Attributes #1, Typ SDK desky: vysokopevnostní+bílá; Object Layer Attributes #1, Způsob opláštění: Oboustranné; Object Layer Attributes #1, Tloušťka izolace (2): 100; Object Layer Attributes #1, Objemová hmotnost izolace: 25; Object Layer Attributes #1, Typ profilu pro SDK: CW 100
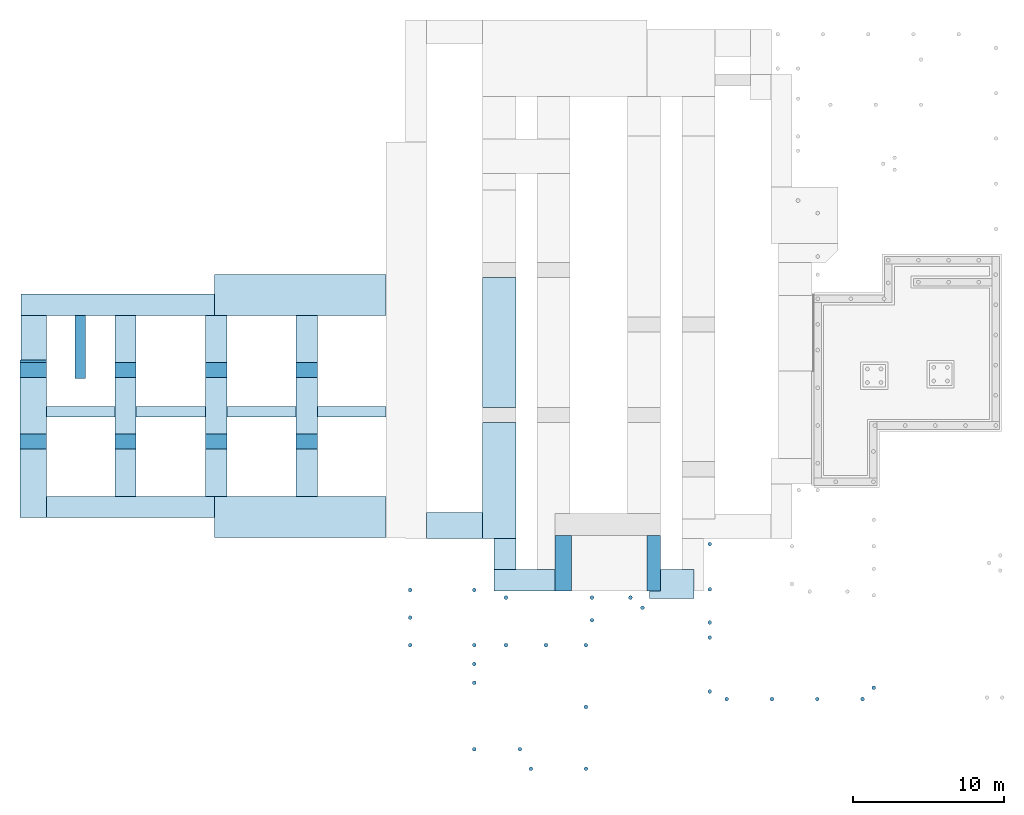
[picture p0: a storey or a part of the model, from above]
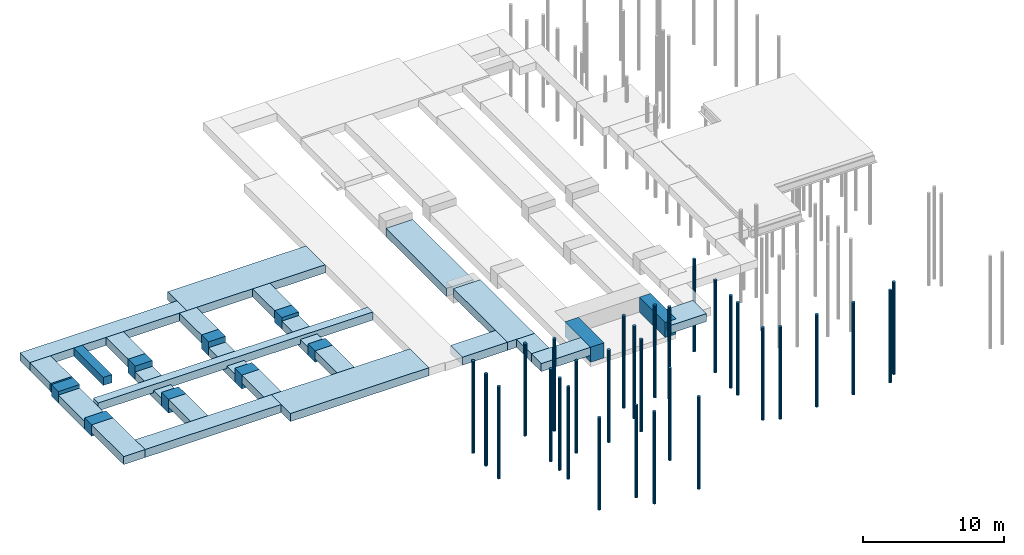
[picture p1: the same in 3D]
Properties of the parts of a building model (IFC4), part 18 of 45

# IfcOpeningElement: Opening (1638)
Name | In | Object Layer Attributes #1, Práce | Object Layer Attributes #1, Allright_Stavebni_dil_ID | Object Layer Attributes #1, Jednotka | Object Layer Attributes #1, Název_objektu | Status | Area (m2) | Depth (m) | Volume (m3) | Height (m) | Width (m)
VZT | Půdorys 1.NP | Suché stavební práce | 1464SVý1096314171 | m3 | Stěna | NEW | 0.02 | 0.125 | 0.002 | 0.1 | 0.2 | NEMSOK - Object Layer Attributes #1, Označení: VZT; Object Layer Attributes #1, Kód prvku: SN07.03.0001; Object Layer Attributes #1, Podlaží: 1.NP; Object Layer Attributes #1, 2D interakce: yes; Object Layer Attributes #1, Staticky nosná konstrukce: no; Object Layer Attributes #1, Požární odolnost: EI 60; Object Layer Attributes #1, Statická funkce: Ne; Object Layer Attributes #1, Vnější průměr: 1010431516015xxxxxxx0; Object Layer Attributes #1, Funkce (venkovní): Ne; Object Layer Attributes #1, Vážená stavební neprůzvučnost: 54; Object Layer Attributes #1, Vlhkostní namáhání oboustranné: Ne; Object Layer Attributes #1, Tloušťka opláštění: 2×12,5; Object Layer Attributes #1, Typ SDK desky: vysokopevnostní+bílá; Object Layer Attributes #1, Způsob opláštění: Oboustranné; Object Layer Attributes #1, Tloušťka izolace (2): 100; Object Layer Attributes #1, Objemová hmotnost izolace: 25; Object Layer Attributes #1, Typ profilu pro SDK: CW 100
VZT | Půdorys 1.NP | Suché stavební práce | 1464SVý1096314212 | m3 | Stěna | NEW | 0.031 | 0.125 | 0.004 | 0.2 | 0.2 | NEMSOK - Object Layer Attributes #1, Označení: VZT; Object Layer Attributes #1, Kód prvku: SN07.03.0001; Object Layer Attributes #1, Podlaží: 1.NP; Object Layer Attributes #1, 2D interakce: yes; Object Layer Attributes #1, Staticky nosná konstrukce: no; Object Layer Attributes #1, Požární odolnost: EI 60; Object Layer Attributes #1, Statická funkce: Ne; Object Layer Attributes #1, Funkce (venkovní): Ne; Object Layer Attributes #1, Vážená stavební neprůzvučnost: 54; Object Layer Attributes #1, Vlhkostní namáhání oboustranné: Ne; Object Layer Attributes #1, Tloušťka opláštění: 2×12,5; Object Layer Attributes #1, Typ SDK desky: vysokopevnostní+bílá; Object Layer Attributes #1, Způsob opláštění: Oboustranné; Object Layer Attributes #1, Tloušťka izolace (2): 100; Object Layer Attributes #1, Objemová hmotnost izolace: 25; Object Layer Attributes #1, Typ profilu pro SDK: CW 100
VZT | Půdorys 1.NP | Suché stavební práce | 1464SVý1096316342 | m3 | Stěna | NEW | 0.031 | 0.125 | 0.004 | 0.2 | 0.2 | NEMSOK - Object Layer Attributes #1, Označení: VZT; Object Layer Attributes #1, Kód prvku: SN07.03.0001; Object Layer Attributes #1, Podlaží: 1.NP; Object Layer Attributes #1, 2D interakce: yes; Object Layer Attributes #1, Staticky nosná konstrukce: no; Object Layer Attributes #1, Požární odolnost: EI 60; Object Layer Attributes #1, Statická funkce: Ne; Object Layer Attributes #1, Funkce (venkovní): Ne; Object Layer Attributes #1, Vážená stavební neprůzvučnost: 54; Object Layer Attributes #1, Vlhkostní namáhání oboustranné: Ne; Object Layer Attributes #1, Tloušťka opláštění: 2×12,5; Object Layer Attributes #1, Typ SDK desky: vysokopevnostní+bílá; Object Layer Attributes #1, Způsob opláštění: Oboustranné; Object Layer Attributes #1, Tloušťka izolace (2): 100; Object Layer Attributes #1, Objemová hmotnost izolace: 25; Object Layer Attributes #1, Typ profilu pro SDK: CW 100
Dveřní otvor | Půdorys 1.NP | Suché stavební práce | 1464Dve1096314018 | m3 | Stěna | NEW | 3.183 | 0.125 | 0.398 | 2.06 | 1.545 | NEMSOK - Object Layer Attributes #1, Směr otevírání dveří: P; Object Layer Attributes #1, Označení: Dveřní otvor; Object Layer Attributes #1, Kód prvku: SN07.03.0001; Object Layer Attributes #1, Podlaží: 1.NP; Object Layer Attributes #1, 2D interakce: yes; Object Layer Attributes #1, Staticky nosná konstrukce: no; Object Layer Attributes #1, Požární odolnost: EI 60; Object Layer Attributes #1, Statická funkce: Ne; Object Layer Attributes #1, Funkce (venkovní): Ne; Object Layer Attributes #1, Vážená stavební neprůzvučnost: 54; Object Layer Attributes #1, Vlhkostní namáhání oboustranné: Ne; Object Layer Attributes #1, Tloušťka opláštění: 2×12,5; Object Layer Attributes #1, Typ SDK desky: vysokopevnostní+bílá; Object Layer Attributes #1, Způsob opláštění: Oboustranné; Object Layer Attributes #1, Tloušťka izolace (2): 100; Object Layer Attributes #1, Objemová hmotnost izolace: 25; Object Layer Attributes #1, Typ profilu pro SDK: CW 100
VZT | Půdorys 1.NP | Suché stavební práce | 1464SVý1096314007 | m3 | Stěna | NEW | 0.031 | 0.125 | 0.004 | 0.2 | 0.2 | NEMSOK - Object Layer Attributes #1, Označení: VZT; Object Layer Attributes #1, Kód prvku: SN07.03.0001; Object Layer Attributes #1, Podlaží: 1.NP; Object Layer Attributes #1, 2D interakce: yes; Object Layer Attributes #1, Staticky nosná konstrukce: no; Object Layer Attributes #1, Požární odolnost: EI 60; Object Layer Attributes #1, Statická funkce: Ne; Object Layer Attributes #1, Funkce (venkovní): Ne; Object Layer Attributes #1, Vážená stavební neprůzvučnost: 54; Object Layer Attributes #1, Vlhkostní namáhání oboustranné: Ne; Object Layer Attributes #1, Tloušťka opláštění: 2×12,5; Object Layer Attributes #1, Typ SDK desky: vysokopevnostní+bílá; Object Layer Attributes #1, Způsob opláštění: Oboustranné; Object Layer Attributes #1, Tloušťka izolace (2): 100; Object Layer Attributes #1, Objemová hmotnost izolace: 25; Object Layer Attributes #1, Typ profilu pro SDK: CW 100
Dveřní otvor | Půdorys 1.NP | Suché stavební práce | 1464Dve1096313955 | m3 | Stěna | NEW | 3.183 | 0.125 | 0.398 | 2.06 | 1.545 | NEMSOK - Object Layer Attributes #1, Směr otevírání dveří: L; Object Layer Attributes #1, Označení: Dveřní otvor; Object Layer Attributes #1, Kód prvku: SN07.03.0001; Object Layer Attributes #1, Podlaží: 1.NP; Object Layer Attributes #1, 2D interakce: yes; Object Layer Attributes #1, Staticky nosná konstrukce: no; Object Layer Attributes #1, Požární odolnost: EI 60; Object Layer Attributes #1, Statická funkce: Ne; Object Layer Attributes #1, Funkce (venkovní): Ne; Object Layer Attributes #1, Vážená stavební neprůzvučnost: 54; Object Layer Attributes #1, Vlhkostní namáhání oboustranné: Ne; Object Layer Attributes #1, Tloušťka opláštění: 2×12,5; Object Layer Attributes #1, Typ SDK desky: vysokopevnostní+bílá; Object Layer Attributes #1, Způsob opláštění: Oboustranné; Object Layer Attributes #1, Tloušťka izolace (2): 100; Object Layer Attributes #1, Objemová hmotnost izolace: 25; Object Layer Attributes #1, Typ profilu pro SDK: CW 100
VZT | Půdorys 1.NP | Suché stavební práce | 1464SVý1096313975 | m3 | Stěna | NEW | 0.031 | 0.125 | 0.004 | 0.2 | 0.2 | NEMSOK - Object Layer Attributes #1, Označení: VZT; Object Layer Attributes #1, Kód prvku: SN07.03.0001; Object Layer Attributes #1, Podlaží: 1.NP; Object Layer Attributes #1, 2D interakce: yes; Object Layer Attributes #1, Staticky nosná konstrukce: no; Object Layer Attributes #1, Požární odolnost: EI 60; Object Layer Attributes #1, Statická funkce: Ne; Object Layer Attributes #1, Funkce (venkovní): Ne; Object Layer Attributes #1, Vážená stavební neprůzvučnost: 54; Object Layer Attributes #1, Vlhkostní namáhání oboustranné: Ne; Object Layer Attributes #1, Tloušťka opláštění: 2×12,5; Object Layer Attributes #1, Typ SDK desky: vysokopevnostní+bílá; Object Layer Attributes #1, Způsob opláštění: Oboustranné; Object Layer Attributes #1, Tloušťka izolace (2): 100; Object Layer Attributes #1, Objemová hmotnost izolace: 25; Object Layer Attributes #1, Typ profilu pro SDK: CW 100
Okenní otvor | Půdorys 1.NP | Suché stavební práce | 1464Okn1096314296 | m3 | Stěna | NEW | 0.16 | 0.1 | 0.016 | 0.4 | 0.4 | NEMSOK - Object Layer Attributes #1, Označení: Okenní otvor; Object Layer Attributes #1, Kód prvku: SN07.03.0001; Object Layer Attributes #1, Podlaží: 1.NP; Object Layer Attributes #1, 2D interakce: yes; Object Layer Attributes #1, Staticky nosná konstrukce: no; Object Layer Attributes #1, Požární odolnost: EI 60; Object Layer Attributes #1, Statická funkce: Ne; Object Layer Attributes #1, Funkce (venkovní): Ne; Object Layer Attributes #1, Vážená stavební neprůzvučnost: 54; Object Layer Attributes #1, Vlhkostní namáhání oboustranné: Ne; Object Layer Attributes #1, Tloušťka opláštění: 2×12,5; Object Layer Attributes #1, Typ SDK desky: vysokopevnostní+bílá; Object Layer Attributes #1, Způsob opláštění: Oboustranné; Object Layer Attributes #1, Tloušťka izolace (2): 100; Object Layer Attributes #1, Objemová hmotnost izolace: 25; Object Layer Attributes #1, Typ profilu pro SDK: CW 100
ZTI | Půdorys 1.NP | Suché stavební práce | 1464SVý1096314304 | m3 | Stěna | NEW | 0.06 | 0.1 | 0.006 | 0.15 | 0.4 | NEMSOK - Object Layer Attributes #1, Označení: ZTI; Object Layer Attributes #1, Kód prvku: SN07.03.0001; Object Layer Attributes #1, Podlaží: 1.NP; Object Layer Attributes #1, 2D interakce: yes; Object Layer Attributes #1, Staticky nosná konstrukce: no; Object Layer Attributes #1, Požární odolnost: EI 60; Object Layer Attributes #1, Statická funkce: Ne; Object Layer Attributes #1, Vnější průměr: 1010431516015xxxxxxx0; Object Layer Attributes #1, Funkce (venkovní): Ne; Object Layer Attributes #1, Vážená stavební neprůzvučnost: 54; Object Layer Attributes #1, Vlhkostní namáhání oboustranné: Ne; Object Layer Attributes #1, Tloušťka opláštění: 2×12,5; Object Layer Attributes #1, Typ SDK desky: vysokopevnostní+bílá; Object Layer Attributes #1, Způsob opláštění: Oboustranné; Object Layer Attributes #1, Tloušťka izolace (2): 100; Object Layer Attributes #1, Objemová hmotnost izolace: 25; Object Layer Attributes #1, Typ profilu pro SDK: CW 100
Dveřní otvor | Půdorys 1.NP | Suché stavební práce | 1464Dve1096314325 | m3 | Stěna | NEW | 4.26 | 0.15 | 0.639 | 2.19 | 1.945 | NEMSOK - Object Layer Attributes #1, Směr otevírání dveří: P; Object Layer Attributes #1, Označení: Dveřní otvor; Object Layer Attributes #1, Kód prvku: SN07.03.0001; Object Layer Attributes #1, Podlaží: 1.NP; Object Layer Attributes #1, 2D interakce: yes; Object Layer Attributes #1, Staticky nosná konstrukce: no; Object Layer Attributes #1, Požární odolnost: EI 60; Object Layer Attributes #1, Statická funkce: Ne; Object Layer Attributes #1, Funkce (venkovní): Ne; Object Layer Attributes #1, Vážená stavební neprůzvučnost: 54; Object Layer Attributes #1, Vlhkostní namáhání oboustranné: Ne; Object Layer Attributes #1, Tloušťka opláštění: 2×12,5; Object Layer Attributes #1, Typ SDK desky: vysokopevnostní+bílá; Object Layer Attributes #1, Způsob opláštění: Oboustranné; Object Layer Attributes #1, Tloušťka izolace (2): 100; Object Layer Attributes #1, Objemová hmotnost izolace: 25; Object Layer Attributes #1, Typ profilu pro SDK: CW 100
Stěnová nika | Půdorys 1.NP | Suché stavební práce | 1464SNi1096313528 | m3 | Stěna | NEW | 0.04 | 0.05 | 0.002 | 0.2 | 0.2 | NEMSOK - Object Layer Attributes #1, Označení: Stěnová nika; Object Layer Attributes #1, Kód prvku: SN07.03.0001; Object Layer Attributes #1, Podlaží: 1.NP; Object Layer Attributes #1, 2D interakce: yes; Object Layer Attributes #1, Staticky nosná konstrukce: no; Object Layer Attributes #1, Požární odolnost: EI 60; Object Layer Attributes #1, Statická funkce: Ne; Object Layer Attributes #1, Funkce (venkovní): Ne; Object Layer Attributes #1, Vážená stavební neprůzvučnost: 54; Object Layer Attributes #1, Vlhkostní namáhání oboustranné: Ne; Object Layer Attributes #1, Tloušťka opláštění: 2×12,5; Object Layer Attributes #1, Typ SDK desky: vysokopevnostní+bílá; Object Layer Attributes #1, Způsob opláštění: Oboustranné; Object Layer Attributes #1, Tloušťka izolace (2): 100; Object Layer Attributes #1, Objemová hmotnost izolace: 25; Object Layer Attributes #1, Typ profilu pro SDK: CW 100
Prostup stěnou | Půdorys 1.NP | Suché stavební práce | 1464SVý1096314327 | m3 | Stěna | NEW | 0.03 | 0.15 | 0.005 | 0.11 | 0.275 | NEMSOK - Object Layer Attributes #1, Označení: Prostup stěnou; Object Layer Attributes #1, Kód prvku: SN07.03.0001; Object Layer Attributes #1, Podlaží: 1.NP; Object Layer Attributes #1, 2D interakce: yes; Object Layer Attributes #1, Staticky nosná konstrukce: no; Object Layer Attributes #1, Požární odolnost: EI 60; Object Layer Attributes #1, Statická funkce: Ne; Object Layer Attributes #1, Vnější průměr: 1010431516015xxxxxxx0; Object Layer Attributes #1, Funkce (venkovní): Ne; Object Layer Attributes #1, Vážená stavební neprůzvučnost: 54; Object Layer Attributes #1, Vlhkostní namáhání oboustranné: Ne; Object Layer Attributes #1, Tloušťka opláštění: 2×12,5; Object Layer Attributes #1, Typ SDK desky: vysokopevnostní+bílá; Object Layer Attributes #1, Způsob opláštění: Oboustranné; Object Layer Attributes #1, Tloušťka izolace (2): 100; Object Layer Attributes #1, Objemová hmotnost izolace: 25; Object Layer Attributes #1, Typ profilu pro SDK: CW 100
Dveřní otvor | Půdorys 1.NP | Suché stavební práce | 1464Dve1096313477 | m3 | Stěna | NEW | 2.12 | 0.125 | 0.265 | 2.12 | 1 | NEMSOK - Object Layer Attributes #1, Směr otevírání dveří: P; Object Layer Attributes #1, Označení: Dveřní otvor; Object Layer Attributes #1, Kód prvku: SN07.03.0001; Object Layer Attributes #1, Podlaží: 1.NP; Object Layer Attributes #1, 2D interakce: yes; Object Layer Attributes #1, Staticky nosná konstrukce: no; Object Layer Attributes #1, Požární odolnost: EI 60; Object Layer Attributes #1, Statická funkce: Ne; Object Layer Attributes #1, Funkce (venkovní): Ne; Object Layer Attributes #1, Vážená stavební neprůzvučnost: 54; Object Layer Attributes #1, Vlhkostní namáhání oboustranné: Ne; Object Layer Attributes #1, Tloušťka opláštění: 2×12,5; Object Layer Attributes #1, Typ SDK desky: vysokopevnostní+bílá; Object Layer Attributes #1, Způsob opláštění: Oboustranné; Object Layer Attributes #1, Tloušťka izolace (2): 100; Object Layer Attributes #1, Objemová hmotnost izolace: 25; Object Layer Attributes #1, Typ profilu pro SDK: CW 100
VZT | Půdorys 1.NP | Suché stavební práce | 1464SVý1096313889 | m3 | Stěna | NEW | 0.165 | 0.125 | 0.021 | 0.3 | 0.55 | NEMSOK - Object Layer Attributes #1, Označení: VZT; Object Layer Attributes #1, Kód prvku: SN07.03.0001; Object Layer Attributes #1, Podlaží: 1.NP; Object Layer Attributes #1, 2D interakce: yes; Object Layer Attributes #1, Staticky nosná konstrukce: no; Object Layer Attributes #1, Požární odolnost: EI 60; Object Layer Attributes #1, Statická funkce: Ne; Object Layer Attributes #1, Vnější průměr: 1010431516015xxxxxxx0; Object Layer Attributes #1, Funkce (venkovní): Ne; Object Layer Attributes #1, Vážená stavební neprůzvučnost: 54; Object Layer Attributes #1, Vlhkostní namáhání oboustranné: Ne; Object Layer Attributes #1, Tloušťka opláštění: 2×12,5; Object Layer Attributes #1, Typ SDK desky: vysokopevnostní+bílá; Object Layer Attributes #1, Způsob opláštění: Oboustranné; Object Layer Attributes #1, Tloušťka izolace (2): 100; Object Layer Attributes #1, Objemová hmotnost izolace: 25; Object Layer Attributes #1, Typ profilu pro SDK: CW 100
Dveřní otvor | Půdorys 1.NP | Suché stavební práce | 1464Dve1096313984 | m3 | Stěna | NEW | 1.908 | 0.125 | 0.238 | 2.12 | 0.9 | NEMSOK - Object Layer Attributes #1, Směr otevírání dveří: P; Object Layer Attributes #1, Označení: Dveřní otvor; Object Layer Attributes #1, Kód prvku: SN07.03.0001; Object Layer Attributes #1, Podlaží: 1.NP; Object Layer Attributes #1, 2D interakce: yes; Object Layer Attributes #1, Staticky nosná konstrukce: no; Object Layer Attributes #1, Požární odolnost: EI 60; Object Layer Attributes #1, Statická funkce: Ne; Object Layer Attributes #1, Funkce (venkovní): Ne; Object Layer Attributes #1, Vážená stavební neprůzvučnost: 54; Object Layer Attributes #1, Vlhkostní namáhání oboustranné: Ne; Object Layer Attributes #1, Tloušťka opláštění: 2×12,5; Object Layer Attributes #1, Typ SDK desky: vysokopevnostní+bílá; Object Layer Attributes #1, Způsob opláštění: Oboustranné; Object Layer Attributes #1, Tloušťka izolace (2): 100; Object Layer Attributes #1, Objemová hmotnost izolace: 25; Object Layer Attributes #1, Typ profilu pro SDK: CW 100
Prostup deskou | Půdorys 1.NP | Betonářské práce | 1466DOt0000000518 | m3 | Otvor v desce | NEW | 0.126 | 0.314 | 0.025 | 0.2 | 0.4 | NEMSOK - Object Layer Attributes #1, Označení: Prostup deskou
Prostup deskou | Půdorys 1.NP | Betonářské práce | 1466DOt0000000525 | m3 | Otvor v desce | NEW | 0.126 | 0.314 | 0.025 | 0.2 | 0.4 | NEMSOK - Object Layer Attributes #1, Označení: Prostup deskou
Prostup deskou | Půdorys 1.NP | Betonářské práce | 1466DOt0000000532 | m3 | Otvor v desce | NEW | 0.126 | 0.314 | 0.025 | 0.2 | 0.4 | NEMSOK - Object Layer Attributes #1, Označení: Prostup deskou
Prostup deskou | Půdorys 1.NP | Betonářské práce | 1466DOt0000000539 | m3 | Otvor v desce | NEW | 0.126 | 0.314 | 0.025 | 0.2 | 0.4 | NEMSOK - Object Layer Attributes #1, Označení: Prostup deskou
Prostup deskou | Půdorys 1.NP | Betonářské práce | 1466DOt0000000561 | m3 | Otvor v desce | NEW | 0.018 | 0.118 | 0.004 | 0.2 | 0.15 | NEMSOK - Object Layer Attributes #1, Označení: Prostup deskou
Prostup deskou | Půdorys 1.NP | Betonářské práce | 1466DOt0000000511 | m3 | Otvor v desce | NEW | 0.018 | 0.118 | 0.004 | 0.2 | 0.15 | NEMSOK - Object Layer Attributes #1, Označení: Prostup deskou
Prostup deskou | Půdorys 1.NP | Betonářské práce | 1466DOt0000001635 | m3 | Otvor v desce | NEW | 0.018 | 0.118 | 0.004 | 0.2 | 0.15 | NEMSOK - Object Layer Attributes #1, Označení: Prostup deskou
Prostup deskou | Půdorys 1.NP | Betonářské práce | 1466DOt0000001672 | m3 | Otvor v desce | NEW | 0.031 | 0.157 | 0.006 | 0.2 | 0.2
Prostup deskou | Půdorys 1.NP | Betonářské práce | 1466DOt0000001711 | m3 | Otvor v desce | NEW | 0.096 | 0.275 | 0.019 | 0.2 | 0.35
Prostup deskou | Půdorys 1.NP | Betonářské práce | 1466DOt0000001706 | m3 | Otvor v desce | NEW | 0.071 | 0.236 | 0.014 | 0.2 | 0.3
Prostup deskou | Půdorys 1.NP | Izolace tepelné | 1466DOt0000000127 | m3 | Otvor v desce | NEW | 0.126 | 0.314 | 0.033 | 0.26 | 0.4
Prostup deskou | Půdorys 1.NP | Izolace tepelné | 1466DOt0000000132 | m3 | Otvor v desce | NEW | 0.126 | 0.314 | 0.033 | 0.26 | 0.4
Prostup deskou | Půdorys 1.NP | Izolace tepelné | 1466DOt0000000137 | m3 | Otvor v desce | NEW | 0.126 | 0.314 | 0.033 | 0.26 | 0.4
Prostup deskou | Půdorys 1.NP | Izolace tepelné | 1466DOt0000000142 | m3 | Otvor v desce | NEW | 0.126 | 0.314 | 0.033 | 0.26 | 0.4
Prostup deskou | Půdorys 1.NP | Izolace tepelné | 1466DOt0000000566 | m3 | Otvor v desce | NEW | 0.018 | 0.118 | 0.005 | 0.26 | 0.15
Prostup deskou | Půdorys 1.NP | Izolace tepelné | 1466DOt0000000499 | m3 | Otvor v desce | NEW | 0.018 | 0.118 | 0.005 | 0.26 | 0.15
Prostup deskou | Půdorys 1.NP | Izolace tepelné | 1466DOt0000001636 | m3 | Otvor v desce | NEW | 0.018 | 0.118 | 0.005 | 0.26 | 0.15
Prostup deskou | Půdorys 1.NP | Izolace tepelné | 1466DOt0000001655 | m3 | Otvor v desce | NEW | 0.031 | 0.157 | 0.008 | 0.26 | 0.2
Prostup deskou | Půdorys 1.NP | Izolace tepelné | 1466DOt0000001716 | m3 | Otvor v desce | NEW | 0.096 | 0.275 | 0.025 | 0.26 | 0.35
Prostup deskou | Půdorys 1.NP | Izolace tepelné | 1466DOt0000001723 | m3 | Otvor v desce | NEW | 0.071 | 0.236 | 0.018 | 0.26 | 0.3
Prostup deskou | Půdorys 1.NP | Izolace tepelné | 1466DOt0000001691 | m3 | Otvor v desce | NEW | 0.018 | 0.118 | 0.005 | 0.26 | 0.15
Prostup deskou | Půdorys 1.NP | Izolace tepelné | 1466DOt0000001696 | m3 | Otvor v desce | NEW | 0.018 | 0.118 | 0.005 | 0.26 | 0.15
Prostup deskou | Půdorys 1.NP | Izolace tepelné | 1466DOt0000001701 | m3 | Otvor v desce | NEW | 0.018 | 0.118 | 0.005 | 0.26 | 0.15
Prostup deskou | Půdorys 1.NP | Betonářské práce | 1466DOt0000000067 | m3 | Otvor v desce | NEW | 0.126 | 0.314 | 0.031 | 0.25 | 0.4 | NEMSOK - Object Layer Attributes #1, Označení: Prostup deskou
Prostup deskou | Půdorys 1.NP | Betonářské práce | 1466DOt0000000072 | m3 | Otvor v desce | NEW | 0.126 | 0.314 | 0.031 | 0.25 | 0.4 | NEMSOK - Object Layer Attributes #1, Označení: Prostup deskou
Prostup deskou | Půdorys 1.NP | Betonářské práce | 1466DOt0000000077 | m3 | Otvor v desce | NEW | 0.126 | 0.314 | 0.031 | 0.25 | 0.4 | NEMSOK - Object Layer Attributes #1, Označení: Prostup deskou
Prostup deskou | Půdorys 1.NP | Betonářské práce | 1466DOt0000000102 | m3 | Otvor v desce | NEW | 0.126 | 0.314 | 0.031 | 0.25 | 0.4 | NEMSOK - Object Layer Attributes #1, Označení: Prostup deskou
Prostup deskou | Půdorys 1.NP | Betonářské práce | 1466DOt0000000117 | m3 | Otvor v desce | NEW | 0.126 | 0.314 | 0.031 | 0.25 | 0.4 | NEMSOK - Object Layer Attributes #1, Označení: Prostup deskou
Prostup deskou | Půdorys 1.NP | Betonářské práce | 1466DOt0000000122 | m3 | Otvor v desce | NEW | 0.126 | 0.314 | 0.031 | 0.25 | 0.4 | NEMSOK - Object Layer Attributes #1, Označení: Prostup deskou
Prostup deskou | Půdorys 1.NP | Betonářské práce | 1466DOt0000000245 | m3 | Otvor v desce | NEW | 1.76 | 1.6 | 0.44 | 0.25 | 1.1 | NEMSOK - Object Layer Attributes #1, Označení: Prostup deskou
Prostup deskou | Půdorys 1.NP | Betonářské práce | 1466DOt0000000546 | m3 | Otvor v desce | NEW | 0.018 | 0.118 | 0.004 | 0.25 | 0.15 | NEMSOK - Object Layer Attributes #1, Označení: Prostup deskou
Prostup deskou | Půdorys 1.NP | Betonářské práce | 1466DOt0000000551 | m3 | Otvor v desce | NEW | 0.018 | 0.118 | 0.004 | 0.25 | 0.15 | NEMSOK - Object Layer Attributes #1, Označení: Prostup deskou
Prostup deskou | Půdorys 1.NP | Betonářské práce | 1466DOt0000000556 | m3 | Otvor v desce | NEW | 0.018 | 0.118 | 0.004 | 0.25 | 0.15 | NEMSOK - Object Layer Attributes #1, Označení: Prostup deskou
Prostup deskou | Půdorys 1.NP | Betonářské práce | 1466DOt0000000603 | m3 | Otvor v desce | NEW | 0.126 | 0.314 | 0.031 | 0.25 | 0.4 | NEMSOK - Object Layer Attributes #1, Označení: Prostup deskou
Prostup deskou | Půdorys 1.NP | Betonářské práce | 1466DOt0000000655 | m3 | Otvor v desce | NEW | 0.126 | 0.314 | 0.031 | 0.25 | 0.4 | NEMSOK - Object Layer Attributes #1, Označení: Prostup deskou
Prostup deskou | Půdorys 1.NP | Betonářské práce | 1466DOt0000000673 | m3 | Otvor v desce | NEW | 0.126 | 0.314 | 0.031 | 0.25 | 0.4 | NEMSOK - Object Layer Attributes #1, Označení: Prostup deskou
Prostup deskou | Půdorys 1.NP | Betonářské práce | 1466DOt0000001235 | m3 | Otvor v desce | NEW | 0.84 | 0.7 | 0.21 | 0.25 | 1.2 | NEMSOK - Object Layer Attributes #1, Označení: Prostup deskou
Prostup deskou | Půdorys 1.NP | Betonářské práce | 1466DOt0000001474 | m3 | Otvor v desce | NEW | 0.126 | 0.314 | 0.031 | 0.25 | 0.4 | NEMSOK - Object Layer Attributes #1, Označení: Prostup deskou
Prostup deskou | Půdorys 1.NP | Betonářské práce | 1466DOt0000001483 | m3 | Otvor v desce | NEW | 0.126 | 0.314 | 0.031 | 0.25 | 0.4 | NEMSOK - Object Layer Attributes #1, Označení: Prostup deskou
Prostup deskou | Půdorys 1.NP | Betonářské práce | 1466DOt0000001545 | m3 | Otvor v desce | NEW | 0.126 | 0.314 | 0.031 | 0.25 | 0.4 | NEMSOK - Object Layer Attributes #1, Označení: Prostup deskou
Prostup deskou | Půdorys 1.NP | Betonářské práce | 1466DOt0000001546 | m3 | Otvor v desce | NEW | 0.126 | 0.314 | 0.031 | 0.25 | 0.4 | NEMSOK - Object Layer Attributes #1, Označení: Prostup deskou
Prostup deskou | Půdorys 1.NP | Betonářské práce | 1466DOt0000001557 | m3 | Otvor v desce | NEW | 0.126 | 0.314 | 0.031 | 0.25 | 0.4 | NEMSOK - Object Layer Attributes #1, Označení: Prostup deskou
Prostup deskou | Půdorys 1.NP | Betonářské práce | 1466DOt0000001558 | m3 | Otvor v desce | NEW | 0.126 | 0.314 | 0.031 | 0.25 | 0.4 | NEMSOK - Object Layer Attributes #1, Označení: Prostup deskou
Prostup deskou | Půdorys 1.NP | Betonářské práce | 1466DOt0000001571 | m3 | Otvor v desce | NEW | 0.126 | 0.314 | 0.031 | 0.25 | 0.4 | NEMSOK - Object Layer Attributes #1, Označení: Prostup deskou
Prostup deskou | Půdorys 1.NP | Betonářské práce | 1466DOt0000001572 | m3 | Otvor v desce | NEW | 0.126 | 0.314 | 0.031 | 0.25 | 0.4 | NEMSOK - Object Layer Attributes #1, Označení: Prostup deskou
Prostup deskou | Půdorys 1.NP | Betonářské práce | 1466DOt0000001583 | m3 | Otvor v desce | NEW | 0.126 | 0.314 | 0.031 | 0.25 | 0.4 | NEMSOK - Object Layer Attributes #1, Označení: Prostup deskou
Prostup deskou | Půdorys 1.NP | Betonářské práce | 1466DOt0000001584 | m3 | Otvor v desce | NEW | 0.126 | 0.314 | 0.031 | 0.25 | 0.4 | NEMSOK - Object Layer Attributes #1, Označení: Prostup deskou
Prostup deskou | Půdorys 1.NP | Betonářské práce | 1466DOt0000001608 | m3 | Otvor v desce | NEW | 0.126 | 0.314 | 0.031 | 0.25 | 0.4 | NEMSOK - Object Layer Attributes #1, Označení: Prostup deskou
Prostup deskou | Půdorys 1.NP | Betonářské práce | 1466DOt0000001607 | m3 | Otvor v desce | NEW | 0.126 | 0.314 | 0.031 | 0.25 | 0.4 | NEMSOK - Object Layer Attributes #1, Označení: Prostup deskou
Prostup deskou | Půdorys 1.NP | Betonářské práce | 1466DOt0000001679 | m3 | Otvor v desce | NEW | 0.031 | 0.157 | 0.008 | 0.25 | 0.2
Prostup deskou | Půdorys 1.NP | Betonářské práce | 1466DOt0000001684 | m3 | Otvor v desce | NEW | 0.031 | 0.157 | 0.008 | 0.25 | 0.2
Prostup deskou | Půdorys 1.NP | Izolace tepelné | 1466DOt0000000573 | m3 | Otvor v desce | NEW | 0.018 | 0.118 | 0.005 | 0.26 | 0.15
Prostup deskou | Půdorys 1.NP | Izolace tepelné | 1466DOt0000000580 | m3 | Otvor v desce | NEW | 0.018 | 0.118 | 0.005 | 0.26 | 0.15
Prostup deskou | Půdorys 1.NP | Izolace tepelné | 1466DOt0000000587 | m3 | Otvor v desce | NEW | 0.018 | 0.118 | 0.005 | 0.26 | 0.15
Prostup deskou | Půdorys 1.NP | Izolace tepelné | 1466DOt0000001230 | m3 | Otvor v desce | NEW | 0.84 | 0.7 | 0.218 | 0.26 | 1.2
Prostup deskou | Půdorys 1.NP | Izolace tepelné | 1466DOt0000000983 | m3 | Otvor v desce | NEW | 0.126 | 0.314 | 0.033 | 0.26 | 0.4
Prostup deskou | Půdorys 1.NP | Izolace tepelné | 1466DOt0000000990 | m3 | Otvor v desce | NEW | 0.126 | 0.314 | 0.033 | 0.26 | 0.4
Prostup deskou | Půdorys 1.NP | Izolace tepelné | 1466DOt0000000911 | m3 | Otvor v desce | NEW | 0.126 | 0.314 | 0.033 | 0.26 | 0.4
Prostup deskou | Půdorys 1.NP | Izolace tepelné | 1466DOt0000000927 | m3 | Otvor v desce | NEW | 0.126 | 0.314 | 0.033 | 0.26 | 0.4
Prostup deskou | Půdorys 1.NP | Izolace tepelné | 1466DOt0000000999 | m3 | Otvor v desce | NEW | 0.126 | 0.314 | 0.033 | 0.26 | 0.4
Prostup deskou | Půdorys 1.NP | Izolace tepelné | 1466DOt0000001473 | m3 | Otvor v desce | NEW | 0.126 | 0.314 | 0.033 | 0.26 | 0.4
Prostup deskou | Půdorys 1.NP | Izolace tepelné | 1466DOt0000001484 | m3 | Otvor v desce | NEW | 0.126 | 0.314 | 0.033 | 0.26 | 0.4
Prostup deskou | Půdorys 1.NP | Izolace tepelné | 1466DOt0000000974 | m3 | Otvor v desce | NEW | 0.126 | 0.314 | 0.033 | 0.26 | 0.4
Prostup deskou | Půdorys 1.NP | Izolace tepelné | 1466DOt0000001544 | m3 | Otvor v desce | NEW | 0.126 | 0.314 | 0.033 | 0.26 | 0.4
Prostup deskou | Půdorys 1.NP | Izolace tepelné | 1466DOt0000001559 | m3 | Otvor v desce | NEW | 0.126 | 0.314 | 0.033 | 0.26 | 0.4
Prostup deskou | Půdorys 1.NP | Izolace tepelné | 1466DOt0000001570 | m3 | Otvor v desce | NEW | 0.126 | 0.314 | 0.033 | 0.26 | 0.4
Prostup deskou | Půdorys 1.NP | Izolace tepelné | 1466DOt0000001585 | m3 | Otvor v desce | NEW | 0.126 | 0.314 | 0.033 | 0.26 | 0.4
Prostup deskou | Půdorys 1.NP | Izolace tepelné | 1466DOt0000001606 | m3 | Otvor v desce | NEW | 0.126 | 0.314 | 0.033 | 0.26 | 0.4
Prostup deskou | Půdorys 1.NP | Izolace tepelné | 1466DOt0000001650 | m3 | Otvor v desce | NEW | 0.031 | 0.157 | 0.008 | 0.26 | 0.2
Prostup deskou | Půdorys 1.NP | Izolace tepelné | 1466DOt0000001645 | m3 | Otvor v desce | NEW | 0.031 | 0.157 | 0.008 | 0.26 | 0.2
Dveřní otvor | Půdorys 2.NP | Betonářské práce | 1552Dve0798441733 | m3 | Dveřní otvor | NEW | 2.02 | 0.5 | 1.01 | 2.02 | 1 | NEMSOK - Object Layer Attributes #1, Směr otevírání dveří: P
Dveřní otvor | Půdorys 2.NP | Betonářské práce | 1552Dve0798419671 | m3 | Dveřní otvor | NEW | 5.85 | 0.5 | 2.925 | 3.25 | 1.8 | NEMSOK - Object Layer Attributes #1, Směr otevírání dveří: -
Okenní otvor | Půdorys 2.NP | Zateplovací systémy | 1552Okn0798420392 | m3 | Okenní otvor | NEW | 3.15 | 0.32 | 1.008 | 2.1 | 1.5
Okenní otvor | Půdorys 2.NP | Zateplovací systémy | 1552Okn0798424123 | m3 | Okenní otvor | NEW | 3.15 | 0.32 | 1.008 | 2.1 | 1.5
Dveřní otvor | Půdorys 2.NP | Betonářské práce | 1552Dve0798428691 | m3 | Dveřní otvor | NEW | 2.475 | 0.32 | 0.792 | 2.75 | 0.9 | NEMSOK - Object Layer Attributes #1, Směr otevírání dveří: L
Dveřní otvor | Půdorys 2.NP | Betonářské práce | 1552Dve0000002162 | m3 | Dveřní otvor | NEW | 2.52 | 0.3 | 0.756 | 2.1 | 1.2 | NEMSOK - Object Layer Attributes #1, Směr otevírání dveří: -
Okenní otvor | Půdorys 2.NP | Zateplovací systémy | 1552Okn0798418997 | m3 | Okenní otvor | NEW | 3.15 | 0.32 | 1.008 | 2.1 | 1.5
Okenní otvor | Půdorys 2.NP | Zateplovací systémy | 1552Okn0798419531 | m3 | Okenní otvor | NEW | 3.15 | 0.32 | 1.008 | 2.1 | 1.5
Okenní otvor | Půdorys 2.NP | Zateplovací systémy | 1552Okn0000002249 | m3 | Okenní otvor | NEW | 3.15 | 0.32 | 1.008 | 2.1 | 1.5
Okenní otvor | Půdorys 2.NP | Zateplovací systémy | 1552Okn0798419476 | m3 | Okenní otvor | NEW | 3.15 | 0.32 | 1.008 | 2.1 | 1.5
Okenní otvor | Půdorys 2.NP | Zateplovací systémy | 1552Okn0798419487 | m3 | Okenní otvor | NEW | 3.15 | 0.32 | 1.008 | 2.1 | 1.5
Okenní otvor | Půdorys 2.NP | Zateplovací systémy | 1552Okn0798419498 | m3 | Okenní otvor | NEW | 3.15 | 0.32 | 1.008 | 2.1 | 1.5
Okenní otvor | Půdorys 2.NP | Zateplovací systémy | 1552Okn0798419509 | m3 | Okenní otvor | NEW | 3.15 | 0.32 | 1.008 | 2.1 | 1.5
Okenní otvor | Půdorys 2.NP | Zateplovací systémy | 1552Okn0798419520 | m3 | Okenní otvor | NEW | 3.15 | 0.32 | 1.008 | 2.1 | 1.5
Okenní otvor | Půdorys 2.NP | Zateplovací systémy | 1552Okn0798420420 | m3 | Okenní otvor | NEW | 3.15 | 0.3 | 0.945 | 2.1 | 1.5
Okenní otvor | Půdorys 2.NP | Zateplovací systémy | 1552Okn0798424356 | m3 | Okenní otvor | NEW | 3.15 | 0.32 | 1.008 | 2.1 | 1.5
Okenní otvor | Půdorys 2.NP | Zateplovací systémy | 1552Okn0798420478 | m3 | Okenní otvor | NEW | 3.15 | 0.32 | 1.008 | 2.1 | 1.5
Okenní otvor | Půdorys 2.NP | Zateplovací systémy | 1552Okn0798420474 | m3 | Okenní otvor | NEW | 3.15 | 0.32 | 1.008 | 2.1 | 1.5
Okenní otvor | Půdorys 2.NP | Zateplovací systémy | 1552Okn0798437030 | m3 | Okenní otvor | NEW | 3.15 | 0.3 | 0.945 | 2.1 | 1.5
Okenní otvor | Půdorys 2.NP | Zateplovací systémy | 1552Okn0798437015 | m3 | Okenní otvor | NEW | 3.15 | 0.3 | 0.945 | 2.1 | 1.5
Okenní otvor | Půdorys 2.NP | Zateplovací systémy | 1552Okn0798419953 | m3 | Okenní otvor | NEW | 3.15 | 0.3 | 0.945 | 2.1 | 1.5
Dveřní otvor | Půdorys 2.NP | Betonářské práce | 1552Dve0798428001 | m3 | Dveřní otvor | NEW | 3.131 | 0.125 | 0.391 | 2.02 | 1.55 | NEMSOK - Object Layer Attributes #1, Směr otevírání dveří: -
Okenní otvor | Půdorys 2.NP | Zateplovací systémy | 1552Okn0798422200 | m3 | Okenní otvor | NEW | 3.15 | 0.32 | 1.008 | 2.1 | 1.5
Okenní otvor | Půdorys 2.NP | Zateplovací systémy | 1552Okn0798422204 | m3 | Okenní otvor | NEW | 3.15 | 0.32 | 1.008 | 2.1 | 1.5
Okenní otvor | Půdorys 2.NP | Zateplovací systémy | 1552Okn0798422207 | m3 | Okenní otvor | NEW | 3.15 | 0.32 | 1.008 | 2.1 | 1.5
Okenní otvor | Půdorys 2.NP | Zateplovací systémy | 1552Okn0798422197 | m3 | Okenní otvor | NEW | 2.52 | 0.32 | 0.806 | 2.1 | 1.2
Okenní otvor | Půdorys 2.NP | Zateplovací systémy | 1552Okn0798422194 | m3 | Okenní otvor | NEW | 2.52 | 0.32 | 0.806 | 2.1 | 1.2
Okenní otvor | Půdorys 2.NP | Zateplovací systémy | 1552Okn0798422191 | m3 | Okenní otvor | NEW | 2.52 | 0.32 | 0.806 | 2.1 | 1.2
Okenní otvor | Půdorys 2.NP | Zateplovací systémy | 1552Okn0798422187 | m3 | Okenní otvor | NEW | 2.52 | 0.32 | 0.806 | 2.1 | 1.2
Dveřní otvor | Půdorys 2.NP | Betonářské práce | 1552Dve0798437681 | m3 | Dveřní otvor | NEW | 2.727 | 0.125 | 0.341 | 2.02 | 1.35 | NEMSOK - Object Layer Attributes #1, Směr otevírání dveří: -
Dveřní otvor | Půdorys 2.NP | Betonářské práce | 1552Dve0798438306 | m3 | Dveřní otvor | NEW | 2.727 | 0.125 | 0.341 | 2.02 | 1.35 | NEMSOK - Object Layer Attributes #1, Směr otevírání dveří: -
Dveřní otvor | Půdorys 2.NP | Betonářské práce | 1552Dve0798438650 | m3 | Dveřní otvor | NEW | 2.02 | 0.125 | 0.253 | 2.02 | 1 | NEMSOK - Object Layer Attributes #1, Směr otevírání dveří: P
Dveřní otvor | Půdorys 2.NP | Betonářské práce | 1552Dve0798433261 | m3 | Dveřní otvor | NEW | 3.503 | 0.25 | 0.876 | 2.26 | 1.55 | NEMSOK - Object Layer Attributes #1, Směr otevírání dveří: -
Dveřní otvor | Půdorys 2.NP | Betonářské práce | 1552Dve0798433259 | m3 | Dveřní otvor | NEW | 3.503 | 0.25 | 0.876 | 2.26 | 1.55 | NEMSOK - Object Layer Attributes #1, Směr otevírání dveří: -
Okenní otvor | Půdorys 2.NP | Zateplovací systémy | 1552Okn0798426588 | m3 | Okenní otvor | NEW | 3.07 | 0.32 | 0.982 | 3.07 | 1
Okenní otvor | Půdorys 2.NP | Zateplovací systémy | 1552Okn0798426590 | m3 | Okenní otvor | NEW | 3.816 | 0.32 | 1.221 | 2.12 | 1.8
Okenní otvor | Půdorys 2.NP | Zateplovací systémy | 1552Okn0798426610 | m3 | Okenní otvor | NEW | 2.25 | 0.32 | 0.72 | 1.5 | 1.5
Okenní otvor | Půdorys 2.NP | Zateplovací systémy | 1552Okn0798426603 | m3 | Okenní otvor | NEW | 2.25 | 0.32 | 0.72 | 1.5 | 1.5
Okenní otvor | Půdorys 2.NP | Zateplovací systémy | 1552Okn0798423975 | m3 | Okenní otvor | NEW | 2.58 | 0.32 | 0.826 | 2.15 | 1.2
Okenní otvor | Půdorys 2.NP | Zateplovací systémy | 1552Okn0798441490 | m3 | Okenní otvor | NEW | 0.72 | 0.125 | 0.09 | 1.2 | 0.6
Okenní otvor | Půdorys 2.NP | Zateplovací systémy | 1552Okn0798454111 | m3 | Okenní otvor | NEW | 1.35 | 0.125 | 0.169 | 0.9 | 1.5
Okenní otvor | Půdorys 2.NP | Zateplovací systémy | 1552Okn0798454134 | m3 | Okenní otvor | NEW | 1.35 | 0.125 | 0.169 | 0.9 | 1.5
Okenní otvor | Půdorys 2.NP | Zateplovací systémy | 1552Okn0798454141 | m3 | Okenní otvor | NEW | 1.35 | 0.125 | 0.169 | 0.9 | 1.5
Okenní otvor | Půdorys 2.NP | Zateplovací systémy | 1552Okn0798443564 | m3 | Okenní otvor | NEW | 0.72 | 0.125 | 0.09 | 1.2 | 0.6
Dveřní otvor | Půdorys 2.NP | Betonářské práce | 1552Dve0798443622 | m3 | Dveřní otvor | NEW | 2.02 | 0.125 | 0.252 | 2.02 | 1 | NEMSOK - Object Layer Attributes #1, Směr otevírání dveří: P
Dveřní otvor | Půdorys 2.NP | Betonářské práce | 1552Dve0798442893 | m3 | Dveřní otvor | NEW | 1.414 | 0.125 | 0.177 | 2.02 | 0.7 | NEMSOK - Object Layer Attributes #1, Směr otevírání dveří: P
Dveřní otvor | Půdorys 2.NP | Betonářské práce | 1552Dve0798442668 | m3 | Dveřní otvor | NEW | 1.414 | 0.125 | 0.177 | 2.02 | 0.7 | NEMSOK - Object Layer Attributes #1, Směr otevírání dveří: P
Dveřní otvor | Půdorys 2.NP | Betonářské práce | 1552Dve0798442812 | m3 | Dveřní otvor | NEW | 1.414 | 0.125 | 0.177 | 2.02 | 0.7 | NEMSOK - Object Layer Attributes #1, Směr otevírání dveří: L
Dveřní otvor | Půdorys 2.NP | Betonářské práce | 1552Dve0798442740 | m3 | Dveřní otvor | NEW | 1.414 | 0.125 | 0.177 | 2.02 | 0.7 | NEMSOK - Object Layer Attributes #1, Směr otevírání dveří: P
Dveřní otvor | Půdorys 2.NP | Betonářské práce | 1552Dve0798443449 | m3 | Dveřní otvor | NEW | 2.02 | 0.125 | 0.253 | 2.02 | 1 | NEMSOK - Object Layer Attributes #1, Směr otevírání dveří: L
Dveřní otvor | Půdorys 2.NP | Betonářské práce | 1552Dve0798443558 | m3 | Dveřní otvor | NEW | 1.54 | 0.125 | 0.192 | 2.2 | 0.7 | NEMSOK - Object Layer Attributes #1, Směr otevírání dveří: -
Dveřní otvor | Půdorys 2.NP | Betonářské práce | 1552Dve0798453592 | m3 | Dveřní otvor | NEW | 1.414 | 0.125 | 0.177 | 2.02 | 0.7 | NEMSOK - Object Layer Attributes #1, Směr otevírání dveří: L
Dveřní otvor | Půdorys 2.NP | Betonářské práce | 1552Dve0798442275 | m3 | Dveřní otvor | NEW | 1.414 | 0.125 | 0.177 | 2.02 | 0.7 | NEMSOK - Object Layer Attributes #1, Směr otevírání dveří: L
Dveřní otvor | Půdorys 2.NP | Betonářské práce | 1552Dve0798442382 | m3 | Dveřní otvor | NEW | 1.414 | 0.125 | 0.177 | 2.02 | 0.7 | NEMSOK - Object Layer Attributes #1, Směr otevírání dveří: P
Okenní otvor | Půdorys 2.NP | Zateplovací systémy | 1552Okn0798443106 | m3 | Okenní otvor | NEW | 0.72 | 0.125 | 0.09 | 1.2 | 0.6
Okenní otvor | Půdorys 2.NP | Zateplovací systémy | 1552Okn0798443145 | m3 | Okenní otvor | NEW | 0.72 | 0.125 | 0.09 | 1.2 | 0.6
Dveřní otvor | Půdorys 2.NP | Betonářské práce | 1552Dve0798442489 | m3 | Dveřní otvor | NEW | 1.414 | 0.125 | 0.177 | 2.02 | 0.7 | NEMSOK - Object Layer Attributes #1, Směr otevírání dveří: P
Dveřní otvor | Půdorys 2.NP | Betonářské práce | 1552Dve0798442561 | m3 | Dveřní otvor | NEW | 1.414 | 0.125 | 0.177 | 2.02 | 0.7 | NEMSOK - Object Layer Attributes #1, Směr otevírání dveří: L
Dveřní otvor | Půdorys 2.NP | Betonářské práce | 1552Dve0798442965 | m3 | Dveřní otvor | NEW | 1.414 | 0.125 | 0.177 | 2.02 | 0.7 | NEMSOK - Object Layer Attributes #1, Směr otevírání dveří: L
Okenní otvor | Půdorys 2.NP | Zateplovací systémy | 1552Okn0798454309 | m3 | Okenní otvor | NEW | 0.72 | 0.125 | 0.09 | 1.2 | 0.6
Okenní otvor | Půdorys 2.NP | Zateplovací systémy | 1552Okn0798443421 | m3 | Okenní otvor | NEW | 0.49 | 0.125 | 0.061 | 0.7 | 0.7
Okenní otvor | Půdorys 2.NP | Zateplovací systémy | 1552Okn0798443919 | m3 | Okenní otvor | NEW | 0.72 | 0.125 | 0.09 | 1.2 | 0.6
Okenní otvor | Půdorys 2.NP | Zateplovací systémy | 1552Okn0798443936 | m3 | Okenní otvor | NEW | 0.72 | 0.125 | 0.09 | 1.2 | 0.6
Prostup stěnou | Půdorys 2.NP | Betonářské práce | 1552SVý0798443723 | m3 | Stěnový výklenek | NEW | 0.237 | 0.32 | 0.076 | 0.55 | 0.55
Prostup stěnou | Půdorys 2.NP | Betonářské práce | 1552SVý0798443694 | m3 | Stěnový výklenek | NEW | 0.42 | 0.32 | 0.134 | 0.7 | 0.6
Okenní otvor | Půdorys 2.NP | Zateplovací systémy | 1552Okn0798419679 | m3 | Okenní otvor | NEW | 5.04 | 0.32 | 1.613 | 2.1 | 2.4
Okenní otvor | Půdorys 2.NP | Zateplovací systémy | 1552Okn0798419804 | m3 | Okenní otvor | NEW | 5.04 | 0.32 | 1.613 | 2.1 | 2.4
Okenní otvor | Půdorys 2.NP | Zateplovací systémy | 1552Okn0798419607 | m3 | Okenní otvor | NEW | 3.15 | 0.32 | 1.008 | 2.1 | 1.5
Okenní otvor | Půdorys 2.NP | Zateplovací systémy | 1552Okn0798419596 | m3 | Okenní otvor | NEW | 3.15 | 0.32 | 1.008 | 2.1 | 1.5
Okenní otvor | Půdorys 2.NP | Zateplovací systémy | 1552Okn0798419575 | m3 | Okenní otvor | NEW | 3.15 | 0.32 | 1.008 | 2.1 | 1.5
Okenní otvor | Půdorys 2.NP | Zateplovací systémy | 1552Okn0798419290 | m3 | Okenní otvor | NEW | 0.75 | 0.32 | 0.24 | 1.25 | 0.6
Okenní otvor | Půdorys 2.NP | Zateplovací systémy | 1552Okn0798419551 | m3 | Okenní otvor | NEW | 0.75 | 0.32 | 0.24 | 1.25 | 0.6
Okenní otvor | Půdorys 2.NP | Zateplovací systémy | 1552Okn0798419545 | m3 | Okenní otvor | NEW | 0.75 | 0.32 | 0.24 | 1.25 | 0.6
Okenní otvor | Půdorys 2.NP | Zateplovací systémy | 1552Okn0798419411 | m3 | Okenní otvor | NEW | 0.75 | 0.32 | 0.24 | 1.25 | 0.6
Dveřní otvor | Půdorys 2.NP | Betonářské práce | 1552Dve0798444389 | m3 | Dveřní otvor | NEW | 3.131 | 0.125 | 0.391 | 2.02 | 1.55 | NEMSOK - Object Layer Attributes #1, Směr otevírání dveří: -
Dveřní otvor | Půdorys 2.NP | Betonářské práce | 1552Dve0798444411 | m3 | Dveřní otvor | NEW | 2.02 | 0.125 | 0.252 | 2.02 | 1 | NEMSOK - Object Layer Attributes #1, Směr otevírání dveří: P
Dveřní otvor | Půdorys 2.NP | Betonářské práce | 1552Dve0798444448 | m2 | Dveřní otvor | NEW | 1.818 | 0.1 | 0.182 | 2.02 | 0.9 | NEMSOK - Object Layer Attributes #1, Směr otevírání dveří: P
Dveřní otvor | Půdorys 2.NP | Betonářské práce | 1552Dve0798444546 | m3 | Dveřní otvor | NEW | 1.818 | 0.125 | 0.227 | 2.02 | 0.9 | NEMSOK - Object Layer Attributes #1, Směr otevírání dveří: P
Dveřní otvor | Půdorys 2.NP | Betonářské práce | 1552Dve0798444840 | m2 | Dveřní otvor | NEW | 1.818 | 0.1 | 0.182 | 2.02 | 0.9 | NEMSOK - Object Layer Attributes #1, Směr otevírání dveří: L
Okenní otvor | Půdorys 2.NP | Zateplovací systémy | 1552Okn0798444919 | m2 | Okenní otvor | NEW | 0.31 | 0.1 | 0.031 | 0.5 | 0.62
Okenní otvor | Půdorys 2.NP | Zateplovací systémy | 1552Okn0798446590 | m3 | Okenní otvor | NEW | 0.281 | 0.3 | 0.084 | 0.15 | 1.875
Okenní otvor | Půdorys 2.NP | Zateplovací systémy | 1552Okn0798446584 | m3 | Okenní otvor | NEW | 6.281 | 0.3 | 1.884 | 3.35 | 1.875
Okenní otvor | Půdorys 2.NP | Zateplovací systémy | 1552Okn0798447221 | m3 | Okenní otvor | NEW | 0.72 | 0.125 | 0.09 | 1.2 | 0.6
Okenní otvor | Půdorys 2.NP | Zateplovací systémy | 1552Okn0798447203 | m3 | Okenní otvor | NEW | 0.72 | 0.125 | 0.09 | 1.2 | 0.6
Okenní otvor | Půdorys 2.NP | Zateplovací systémy | 1552Okn0798450503 | m2 | Okenní otvor | NEW | 3 | 0.4 | 0.3 | 2 | 1.5 | NEMSOK - Object Layer Attributes #2, Status: Nový; Object Layer Attributes #2, Práce: Zateplovací systémy; Object Layer Attributes #2, Allright_Stavebni_dil_ID: 1552Okn0798450504; Object Layer Attributes #2, Jednotka: m3; Object Layer Attributes #2, Název_objektu: Okenní otvor
Dveřní otvor | Půdorys 2.NP | Betonářské práce | 1552Dve0798450893 | m3 | Dveřní otvor | NEW | 2.691 | 0.5 | 1.346 | 2.07 | 1.3 | NEMSOK - Object Layer Attributes #1, Směr otevírání dveří: -
Dveřní otvor | Půdorys 2.NP | Betonářské práce | 1552Dve0798450894 | m3 | Dveřní otvor | NEW | 2.691 | 0.5 | 1.346 | 2.07 | 1.3 | NEMSOK - Object Layer Attributes #1, Směr otevírání dveří: -
Prostup stěnou | Půdorys 2.NP | Zednické práce | 1552SVý0798453446 | m3 | Stěnový výklenek | NEW | 0.022 | 0.4 | 0.009 | 0.15 | 0.15
Prostup stěnou | Půdorys 2.NP | Zednické práce | 1552SVý0798453444 | m3 | Stěnový výklenek | NEW | 0.023 | 0.4 | 0.009 | 0.15 | 0.15
Prostup stěnou | Půdorys 2.NP | Zednické práce | 1552SVý0798453386 | m3 | Stěnový výklenek | NEW | 0.023 | 0.4 | 0.009 | 0.15 | 0.15
Prostup stěnou | Půdorys 2.NP | Zednické práce | 1552SVý0798453402 | m3 | Stěnový výklenek | NEW | 0.023 | 0.4 | 0.009 | 0.15 | 0.15
Prostup stěnou | Půdorys 2.NP | Zednické práce | 1552SVý0798453392 | m3 | Stěnový výklenek | NEW | 0.023 | 0.4 | 0.009 | 0.15 | 0.15
Prostup stěnou | Půdorys 2.NP | Zednické práce | 1552SVý0798453416 | m3 | Stěnový výklenek | NEW | 0.023 | 0.4 | 0.009 | 0.15 | 0.15
Prostup stěnou | Půdorys 2.NP | Zednické práce | 1552SVý0798453418 | m3 | Stěnový výklenek | NEW | 0.023 | 0.4 | 0.009 | 0.15 | 0.15
Prostup stěnou | Půdorys 2.NP | Zednické práce | 1552SVý0798453434 | m3 | Stěnový výklenek | NEW | 0.023 | 0.4 | 0.009 | 0.15 | 0.15
Prostup stěnou | Půdorys 2.NP | Zednické práce | 1552SVý0798453365 | m3 | Stěnový výklenek | NEW | 0.023 | 0.4 | 0.009 | 0.15 | 0.15
Okenní otvor | Půdorys 2.NP | Zateplovací systémy | 1552Okn0798424387 | m2 | Okenní otvor | NEW | 3 | 0.4 | 0.3 | 2 | 1.5 | NEMSOK - Object Layer Attributes #2, Status: Nový; Object Layer Attributes #2, Práce: Zateplovací systémy; Object Layer Attributes #2, Allright_Stavebni_dil_ID: 1552Okn0798448402; Object Layer Attributes #2, Jednotka: m3; Object Layer Attributes #2, Název_objektu: Okenní otvor
Okenní otvor | Půdorys 2.NP | Zateplovací systémy | 1552Okn0798435275 | m2 | Okenní otvor | NEW | 3 | 0.4 | 0.3 | 2 | 1.5 | NEMSOK - Object Layer Attributes #2, Status: Nový; Object Layer Attributes #2, Práce: Zateplovací systémy; Object Layer Attributes #2, Allright_Stavebni_dil_ID: 1552Okn0798448407; Object Layer Attributes #2, Jednotka: m3; Object Layer Attributes #2, Název_objektu: Okenní otvor
Dveřní otvor | Půdorys 2.NP | Betonářské práce | 1552Dve0798453471 | m2 | Dveřní otvor | NEW | 2.02 | 0.1 | 0.202 | 2.02 | 1 | NEMSOK - Object Layer Attributes #1, Směr otevírání dveří: P
Dveřní otvor | Půdorys 2.NP | Betonářské práce | 1552Dve0798453638 | m2 | Dveřní otvor | NEW | 1.818 | 0.1 | 0.182 | 2.02 | 0.9 | NEMSOK - Object Layer Attributes #1, Směr otevírání dveří: L
Prostup deskou | Půdorys 2.NP | Betonářské práce | 1554DOt0000000613 | m3 | Otvor v desce | NEW | 0.1 | 0.5 | 0.025 | 0.25 | 0.2
Prostup deskou | Půdorys 2.NP | Betonářské práce | 1554DOt0000000583 | m3 | Otvor v desce | NEW | 0.385 | 0.7 | 0.096 | 0.25 | 0.55
Prostup deskou | Půdorys 2.NP | Betonářské práce | 1554DOt0000000585 | m3 | Otvor v desce | NEW | 0.4 | 0.8 | 0.1 | 0.25 | 0.5
Prostup deskou | Půdorys 2.NP | Betonářské práce | 1554DOt0000000581 | m3 | Otvor v desce | NEW | 0.38 | 0.4 | 0.095 | 0.25 | 0.95
Prostup deskou | Půdorys 2.NP | Betonářské práce | 1554DOt0000000587 | m3 | Otvor v desce | NEW | 0.495 | 0.9 | 0.124 | 0.25 | 0.55
Prostup deskou | Půdorys 2.NP | Betonářské práce | 1554DOt0000000535 | m3 | Otvor v desce | NEW | 0.81 | 2.7 | 0.203 | 0.25 | 0.3
Prostup deskou | Půdorys 2.NP | Betonářské práce | 1554DOt0000000572 | m3 | Otvor v desce | NEW | 0.25 | 0.5 | 0.062 | 0.25 | 0.5
Prostup deskou | Půdorys 2.NP | Betonářské práce | 1554DOt0000000570 | m3 | Otvor v desce | NEW | 0.2 | 0.5 | 0.05 | 0.25 | 0.4
Prostup deskou | Půdorys 2.NP | Betonářské práce | 1554DOt0000000595 | m3 | Otvor v desce | NEW | 0.33 | 0.6 | 0.082 | 0.25 | 0.55
Prostup deskou | Půdorys 2.NP | Betonářské práce | 1554DOt0000000599 | m3 | Otvor v desce | NEW | 0.35 | 0.7 | 0.087 | 0.25 | 0.5
Prostup deskou | Půdorys 2.NP | Betonářské práce | 1554DOt0000000917 | m3 | Otvor v desce | NEW | 0.096 | 0.275 | 0.024 | 0.25 | 0.35
Prostup deskou | Půdorys 2.NP | Betonářské práce | 1554DOt0000000919 | m3 | Otvor v desce | NEW | 0.36 | 0.6 | 0.09 | 0.25 | 0.6
Prostup deskou | Půdorys 2.NP | Betonářské práce | 1554DOt0000000944 | m3 | Otvor v desce | NEW | 0.09 | 0.3 | 0.023 | 0.25 | 0.3
Prostup deskou | Půdorys 2.NP | Betonářské práce | 1554DOt0000000966 | m3 | Otvor v desce | NEW | 0.09 | 0.3 | 0.023 | 0.25 | 0.3
Prostup deskou | Půdorys 2.NP | Betonářské práce | 1554DOt0000000993 | m3 | Otvor v desce | NEW | 0.04 | 0.2 | 0.01 | 0.25 | 0.2
Prostup deskou | Půdorys 2.NP | Betonářské práce | 1554DOt0000001020 | m3 | Otvor v desce | NEW | 0.04 | 0.2 | 0.01 | 0.25 | 0.2
Prostup deskou | Půdorys 2.NP | Betonářské práce | 1554DOt0000001033 | m3 | Otvor v desce | NEW | 0.04 | 0.2 | 0.01 | 0.25 | 0.2
Prostup deskou | Půdorys 2.NP | Betonářské práce | 1554DOt0000001179 | m3 | Otvor v desce | NEW | 0.018 | 0.118 | 0.004 | 0.25 | 0.15
Prostup deskou | Půdorys 2.NP | Betonářské práce | 1554DOt0000001178 | m3 | Otvor v desce | NEW | 0.018 | 0.118 | 0.004 | 0.25 | 0.15
Prostup deskou | Půdorys 2.NP | Betonářské práce | 1554DOt0000001177 | m3 | Otvor v desce | NEW | 0.018 | 0.118 | 0.004 | 0.25 | 0.15
Prostup deskou | Půdorys 2.NP | Betonářské práce | 1554DOt0000001176 | m3 | Otvor v desce | NEW | 0.018 | 0.118 | 0.004 | 0.25 | 0.15
Prostup deskou | Půdorys 2.NP | Betonářské práce | 1554DOt0000001175 | m3 | Otvor v desce | NEW | 0.018 | 0.118 | 0.004 | 0.25 | 0.15
Prostup deskou | Půdorys 2.NP | Betonářské práce | 1554DOt0000001174 | m3 | Otvor v desce | NEW | 0.018 | 0.118 | 0.004 | 0.25 | 0.15
Prostup deskou | Půdorys 2.NP | Betonářské práce | 1554DOt0000001199 | m3 | Otvor v desce | NEW | 0.018 | 0.118 | 0.004 | 0.25 | 0.15
Prostup deskou | Půdorys 2.NP | Betonářské práce | 1554DOt0000001198 | m3 | Otvor v desce | NEW | 0.018 | 0.118 | 0.004 | 0.25 | 0.15
Prostup deskou | Půdorys 2.NP | Betonářské práce | 1554DOt0000001197 | m3 | Otvor v desce | NEW | 0.018 | 0.118 | 0.004 | 0.25 | 0.15
Prostup deskou | Půdorys 2.NP | Betonářské práce | 1554DOt0000001196 | m3 | Otvor v desce | NEW | 0.018 | 0.118 | 0.004 | 0.25 | 0.15
Prostup deskou | Půdorys 2.NP | Betonářské práce | 1554DOt0000001195 | m3 | Otvor v desce | NEW | 0.018 | 0.118 | 0.004 | 0.25 | 0.15
Prostup deskou | Půdorys 2.NP | Betonářské práce | 1554DOt0000001194 | m3 | Otvor v desce | NEW | 0.018 | 0.118 | 0.004 | 0.25 | 0.15
Prostup deskou | Půdorys 2.NP | Betonářské práce | 1554DOt0000001219 | m3 | Otvor v desce | NEW | 0.018 | 0.118 | 0.004 | 0.25 | 0.15
Prostup deskou | Půdorys 2.NP | Betonářské práce | 1554DOt0000001218 | m3 | Otvor v desce | NEW | 0.018 | 0.118 | 0.004 | 0.25 | 0.15
Prostup deskou | Půdorys 2.NP | Betonářské práce | 1554DOt0000001217 | m3 | Otvor v desce | NEW | 0.018 | 0.118 | 0.004 | 0.25 | 0.15
Prostup deskou | Půdorys 2.NP | Betonářské práce | 1554DOt0000001216 | m3 | Otvor v desce | NEW | 0.018 | 0.118 | 0.004 | 0.25 | 0.15
Prostup deskou | Půdorys 2.NP | Betonářské práce | 1554DOt0000001215 | m3 | Otvor v desce | NEW | 0.018 | 0.118 | 0.004 | 0.25 | 0.15
Prostup deskou | Půdorys 2.NP | Betonářské práce | 1554DOt0000001214 | m3 | Otvor v desce | NEW | 0.018 | 0.118 | 0.004 | 0.25 | 0.15
Prostup deskou | Půdorys 2.NP | Betonářské práce | 1554DOt0000001361 | m3 | Otvor v desce | NEW | 0.07 | 0.2 | 0.007 | 0.1 | 0.35
Prostup deskou | Půdorys 2.NP | Betonářské práce | 1554DOt0000001363 | m3 | Otvor v desce | NEW | 0.01 | 0.1 | 0.001 | 0.1 | 0.1
Prostup deskou | Půdorys 2.NP | Betonářské práce | 1554DOt0000001359 | m3 | Otvor v desce | NEW | 0.27 | 0.9 | 0.027 | 0.1 | 0.3
Prostup deskou | Půdorys 2.NP | Betonářské práce | 1554DOt0000001124 | m3 | Otvor v desce | NEW | 0.018 | 0.118 | 0.004 | 0.25 | 0.15
Prostup deskou | Půdorys 2.NP | Betonářské práce | 1554DOt0000001129 | m3 | Otvor v desce | NEW | 0.018 | 0.118 | 0.004 | 0.25 | 0.15
Prostup deskou | Půdorys 2.NP | Betonářské práce | 1554DOt0000001134 | m3 | Otvor v desce | NEW | 0.018 | 0.118 | 0.004 | 0.25 | 0.15
Prostup deskou | Půdorys 2.NP | Betonářské práce | 1554DOt0000001139 | m3 | Otvor v desce | NEW | 0.018 | 0.118 | 0.004 | 0.25 | 0.15
Prostup deskou | Půdorys 2.NP | Betonářské práce | 1554DOt0000001144 | m3 | Otvor v desce | NEW | 0.018 | 0.118 | 0.004 | 0.25 | 0.15
Prostup deskou | Půdorys 2.NP | Betonářské práce | 1554DOt0000001149 | m3 | Otvor v desce | NEW | 0.018 | 0.118 | 0.004 | 0.25 | 0.15
Prostup deskou | Půdorys 2.NP | Betonářské práce | 1554DOt0000001159 | m3 | Otvor v desce | NEW | 0.018 | 0.118 | 0.004 | 0.25 | 0.15
Prostup deskou | Půdorys 2.NP | Betonářské práce | 1554DOt0000001158 | m3 | Otvor v desce | NEW | 0.018 | 0.118 | 0.004 | 0.25 | 0.15
Prostup deskou | Půdorys 2.NP | Betonářské práce | 1554DOt0000001157 | m3 | Otvor v desce | NEW | 0.018 | 0.118 | 0.004 | 0.25 | 0.15
Prostup deskou | Půdorys 2.NP | Betonářské práce | 1554DOt0000001156 | m3 | Otvor v desce | NEW | 0.018 | 0.118 | 0.004 | 0.25 | 0.15
Prostup deskou | Půdorys 2.NP | Betonářské práce | 1554DOt0000001155 | m3 | Otvor v desce | NEW | 0.018 | 0.118 | 0.004 | 0.25 | 0.15
Prostup deskou | Půdorys 2.NP | Betonářské práce | 1554DOt0000001154 | m3 | Otvor v desce | NEW | 0.018 | 0.118 | 0.004 | 0.25 | 0.15
Prostup deskou | Půdorys 2.NP | Betonářské práce | 1554DOt0000001101 | m3 | Otvor v desce | NEW | 0.04 | 0.2 | 0.01 | 0.25 | 0.2
Prostup deskou | Půdorys 2.NP | Betonářské práce | 1554DOt0000001096 | m3 | Otvor v desce | NEW | 0.09 | 0.3 | 0.023 | 0.25 | 0.3
Prostup deskou | Půdorys 2.NP | Betonářské práce | 1554DOt0000001091 | m3 | Otvor v desce | NEW | 0.04 | 0.2 | 0.01 | 0.25 | 0.2
Prostup deskou | Půdorys 2.NP | Betonářské práce | 1554DOt0000001392 | m3 | Otvor v desce | NEW | 0.315 | 0.5 | 0.079 | 0.25 | 0.63
Prostup deskou | Půdorys 2.NP | Betonářské práce | 1554DOt0000001417 | m3 | Otvor v desce | NEW | 0.315 | 0.5 | 0.079 | 0.25 | 0.63
Prostup deskou | Půdorys 2.NP | Betonářské práce | 1554DOt0000001042 | m3 | Otvor v desce | NEW | 0.09 | 0.3 | 0.023 | 0.25 | 0.3
Prostup deskou | Půdorys 2.NP | Betonářské práce | 1554DOt0000001051 | m3 | Otvor v desce | NEW | 0.09 | 0.3 | 0.023 | 0.25 | 0.3
Prostup deskou | Půdorys 2.NP | Betonářské práce | 1554DOt0000001010 | m3 | Otvor v desce | NEW | 0.04 | 0.2 | 0.01 | 0.25 | 0.2
Prostup deskou | Půdorys 2.NP | Betonářské práce | 1554DOt0000000971 | m3 | Otvor v desce | NEW | 0.09 | 0.3 | 0.023 | 0.25 | 0.3
Prostup deskou | Půdorys 2.NP | Betonářské práce | 1554DOt0000000976 | m3 | Otvor v desce | NEW | 0.24 | 0.4 | 0.06 | 0.25 | 0.6
Prostup deskou | Půdorys 2.NP | Betonářské práce | 1554DOt0000001015 | m3 | Otvor v desce | NEW | 0.04 | 0.2 | 0.01 | 0.25 | 0.2
Prostup deskou | Půdorys 2.NP | Betonářské práce | 1554DOt0000001077 | m3 | Otvor v desce | NEW | 0.09 | 0.3 | 0.023 | 0.25 | 0.3
Prostup deskou | Půdorys 2.NP | Betonářské práce | 1554DOt0000000525 | m3 | Otvor v desce | NEW | 0.1 | 0.5 | 0.025 | 0.25 | 0.2
Prostup deskou | Půdorys 2.NP | Betonářské práce | 1554DOt0000000531 | m3 | Otvor v desce | NEW | 0.385 | 0.7 | 0.096 | 0.25 | 0.55
Prostup deskou | Půdorys 2.NP | Betonářské práce | 1554DOt0000000533 | m3 | Otvor v desce | NEW | 0.14 | 0.7 | 0.035 | 0.25 | 0.2
Prostup deskou | Půdorys 2.NP | Betonářské práce | 1554DOt0000000529 | m3 | Otvor v desce | NEW | 2.992 | 1.05 | 0.748 | 0.25 | 2.85
Prostup deskou | Půdorys 2.NP | Betonářské práce | 1554DOt0000000527 | m3 | Otvor v desce | NEW | 0.21 | 1.05 | 0.053 | 0.25 | 0.2
Prostup deskou | Půdorys 2.NP | Betonářské práce | 1554DOt0000000523 | m3 | Otvor v desce | NEW | 0.3 | 0.6 | 0.075 | 0.25 | 0.5
Prostup deskou | Půdorys 2.NP | Betonářské práce | 1554DOt0000000521 | m3 | Otvor v desce | NEW | 0.45 | 0.3 | 0.112 | 0.25 | 1.5
Okenní otvor | Půdorys 2.NP | Zateplovací systémy | 1564Okn0798463278 | m3 | Okenní otvor | NEW | 3.15 | 0.3 | 0.945 | 2.1 | 1.5
Okenní otvor | Půdorys 2.NP | Zateplovací systémy | 1564Okn0798468905 | m3 | Okenní otvor | NEW | 5.936 | 0.3 | 1.781 | 2.12 | 2.8
Prostup deskou | Půdorys 2.NP | Izolace tepelné | 1564DOt0798461376 | m3 | Otvor v desce | NEW | 0.096 | 0.275 | 0.016 | 0.17 | 0.35
Prostup deskou | Půdorys 2.NP | Izolace tepelné | 1564DOt0798461371 | m3 | Otvor v desce | NEW | 0.096 | 0.275 | 0.012 | 0.12 | 0.35
Prostup deskou | Půdorys 2.NP | Izolace tepelné | 1564DOt0798461366 | m3 | Otvor v desce | NEW | 0.096 | 0.275 | 0.011 | 0.111 | 0.35
Prostup deskou | Půdorys 2.NP | Izolace tepelné | 1564DOt0798461361 | m3 | Otvor v desce | NEW | 0.096 | 0.275 | 0.015 | 0.153 | 0.35
Prostup stěnou | Půdorys 2.NP | Betonářské práce | 1564SVý0798466663 | m3 | Stěnový výklenek | NEW | 2.56 | 0.25 | 0.64 | 1.6 | 1.6 | NEMSOK - Object Layer Attributes #1, Označení: Prostup stěnou
Prostup stěnou | Půdorys 2.NP | Suché stavební práce | 1564SVý0798466930 | m3 | Stěnový výklenek | NEW | 2.32 | 0.3 | 0.696 | 1.6 | 1.45 | NEMSOK - Object Layer Attributes #1, Označení: Prostup stěnou
Okenní otvor | Půdorys 2.NP | Zateplovací systémy | 1564Okn0798450724 | m3 | Okenní otvor | NEW | 3 | 0.1 | 0.3 | 2 | 1.5 | NEMSOK - Object Layer Attributes #1, Označení: Okenní otvor
Prostup deskou | Půdorys 2.NP | Izolace tepelné | 1564DOt0798461134 | m3 | Otvor v desce | NEW | 0.096 | 0.275 | 0.02 | 0.207 | 0.35
Prostup deskou | Půdorys 2.NP | Izolace tepelné | 1564DOt0798461129 | m3 | Otvor v desce | NEW | 0.096 | 0.275 | 0.013 | 0.132 | 0.35
Prostup deskou | Půdorys 2.NP | Izolace tepelné | 1564DOt0798461084 | m3 | Otvor v desce | NEW | 0.096 | 0.275 | 0.004 | 0.045 | 0.35
Prostup deskou | Půdorys 2.NP | Izolace tepelné | 1564DOt0798461089 | m3 | Otvor v desce | NEW | 0.096 | 0.275 | 0.008 | 0.088 | 0.35
Prostup deskou | Půdorys 2.NP | Izolace tepelné | 1564DOt0798461094 | m3 | Otvor v desce | NEW | 0.096 | 0.275 | 0.019 | 0.196 | 0.35
Prostup deskou | Půdorys 2.NP | Izolace tepelné | 1564DOt0798461119 | m3 | Otvor v desce | NEW | 0.096 | 0.275 | 0.015 | 0.156 | 0.35
Prostup deskou | Půdorys 2.NP | Izolace tepelné | 1564DOt0798461124 | m3 | Otvor v desce | NEW | 0.096 | 0.275 | 0.005 | 0.048 | 0.35
Prostup deskou | Půdorys 2.NP | Izolace tepelné | 1564DOt0798461114 | m3 | Otvor v desce | NEW | 0.096 | 0.275 | 0.015 | 0.156 | 0.35
Prostup deskou | Půdorys 2.NP | Izolace tepelné | 1564DOt0798461109 | m3 | Otvor v desce | NEW | 0.096 | 0.275 | 0.015 | 0.151 | 0.35
Prostup deskou | Půdorys 2.NP | Izolace tepelné | 1564DOt0798461104 | m3 | Otvor v desce | NEW | 0.096 | 0.275 | 0.019 | 0.196 | 0.35
Prostup deskou | Půdorys 2.NP | Izolace tepelné | 1564DOt0798461099 | m3 | Otvor v desce | NEW | 0.096 | 0.275 | 0.015 | 0.151 | 0.35
Prostup deskou | Půdorys 2.NP | Izolace tepelné | 1564DOt0798460995 | m3 | Otvor v desce | NEW | 0.096 | 0.275 | 0.015 | 0.151 | 0.35
Prostup deskou | Půdorys 2.NP | Izolace tepelné | 1564DOt0798461139 | m3 | Otvor v desce | NEW | 0.096 | 0.275 | 0.006 | 0.066 | 0.35
Prostup deskou | Půdorys 2.NP | Izolace tepelné | 1564DOt0798473468 | m3 | Otvor v desce | NEW | 0.84 | 0.7 | 0.084 | 0.1 | 1.2
Okenní otvor | Půdorys 3.NP | Zateplovací systémy | 1652Okn0798426526 | m3 | Okenní otvor | NEW | 2.775 | 0.32 | 0.888 | 1.85 | 1.5
Okenní otvor | Půdorys 3.NP | Zateplovací systémy | 1652Okn0798426115 | m3 | Okenní otvor | NEW | 2.775 | 0.32 | 0.888 | 1.85 | 1.5
Okenní otvor | Půdorys 3.NP | Zateplovací systémy | 1652Okn0798426121 | m3 | Okenní otvor | NEW | 2.775 | 0.32 | 0.888 | 1.85 | 1.5
Okenní otvor | Půdorys 3.NP | Zateplovací systémy | 1652Okn0798426669 | m3 | Okenní otvor | NEW | 2.7 | 0.3 | 0.81 | 1.8 | 1.5
Okenní otvor | Půdorys 3.NP | Zateplovací systémy | 1652Okn0798436345 | m3 | Okenní otvor | NEW | 2.7 | 0.3 | 0.81 | 1.8 | 1.5
Okenní otvor | Půdorys 3.NP | Zateplovací systémy | 1652Okn0798436360 | m3 | Okenní otvor | NEW | 2.7 | 0.3 | 0.81 | 1.8 | 1.5
Okenní otvor | Půdorys 3.NP | Zateplovací systémy | 1652Okn0798431622 | m3 | Okenní otvor | NEW | 2.7 | 0.32 | 0.864 | 1.8 | 1.5
Okenní otvor | Půdorys 3.NP | Zateplovací systémy | 1652Okn0798431791 | m3 | Okenní otvor | NEW | 2.7 | 0.32 | 0.864 | 1.8 | 1.5
Okenní otvor | Půdorys 3.NP | Zateplovací systémy | 1652Okn0798431789 | m3 | Okenní otvor | NEW | 2.7 | 0.32 | 0.864 | 1.8 | 1.5
Dveřní otvor | Půdorys 3.NP | Betonářské práce | 1652Dve0798431788 | m3 | Dveřní otvor | NEW | 2.475 | 0.32 | 0.792 | 2.75 | 0.9 | NEMSOK - Object Layer Attributes #1, Směr otevírání dveří: L
Okenní otvor | Půdorys 3.NP | Zateplovací systémy | 1652Okn0798431786 | m3 | Okenní otvor | NEW | 2.7 | 0.32 | 0.864 | 1.8 | 1.5
Okenní otvor | Půdorys 3.NP | Zateplovací systémy | 1652Okn0798431793 | m3 | Okenní otvor | NEW | 2.7 | 0.32 | 0.864 | 1.8 | 1.5
Okenní otvor | Půdorys 3.NP | Zateplovací systémy | 1652Okn0798431783 | m3 | Okenní otvor | NEW | 2.7 | 0.32 | 0.864 | 1.8 | 1.5
Dveřní otvor | Půdorys 3.NP | Betonářské práce | 1652Dve0798431785 | m3 | Dveřní otvor | NEW | 2.475 | 0.32 | 0.792 | 2.75 | 0.9 | NEMSOK - Object Layer Attributes #1, Směr otevírání dveří: P
Dveřní otvor | Půdorys 3.NP | Betonářské práce | 1652Dve0798434487 | m3 | Dveřní otvor | NEW | 3.503 | 0.25 | 0.876 | 2.26 | 1.55 | NEMSOK - Object Layer Attributes #1, Směr otevírání dveří: -
Dveřní otvor | Půdorys 3.NP | Betonářské práce | 1652Dve0798434485 | m3 | Dveřní otvor | NEW | 3.503 | 0.25 | 0.876 | 2.26 | 1.55 | NEMSOK - Object Layer Attributes #1, Směr otevírání dveří: -
Okenní otvor | Půdorys 3.NP | Zateplovací systémy | 1652Okn0798431130 | m3 | Okenní otvor | NEW | 2.16 | 0.32 | 0.691 | 1.8 | 1.2
Okenní otvor | Půdorys 3.NP | Zateplovací systémy | 1652Okn0798431140 | m3 | Okenní otvor | NEW | 2.16 | 0.32 | 0.691 | 1.8 | 1.2
Okenní otvor | Půdorys 3.NP | Zateplovací systémy | 1652Okn0798431152 | m3 | Okenní otvor | NEW | 2.16 | 0.32 | 0.691 | 1.8 | 1.2
Okenní otvor | Půdorys 3.NP | Zateplovací systémy | 1652Okn0798431178 | m3 | Okenní otvor | NEW | 2.16 | 0.32 | 0.691 | 1.8 | 1.2
Okenní otvor | Půdorys 3.NP | Zateplovací systémy | 1652Okn0798426582 | m3 | Okenní otvor | NEW | 2.7 | 0.32 | 0.864 | 1.8 | 1.5
Okenní otvor | Půdorys 3.NP | Zateplovací systémy | 1652Okn0798426586 | m3 | Okenní otvor | NEW | 2.7 | 0.32 | 0.864 | 1.8 | 1.5
Okenní otvor | Půdorys 3.NP | Zateplovací systémy | 1652Okn0798431095 | m3 | Okenní otvor | NEW | 2.7 | 0.32 | 0.864 | 1.8 | 1.5
Okenní otvor | Půdorys 3.NP | Zateplovací systémy | 1652Okn0798431107 | m3 | Okenní otvor | NEW | 2.7 | 0.32 | 0.864 | 1.8 | 1.5
Okenní otvor | Půdorys 3.NP | Zateplovací systémy | 1652Okn0798431118 | m3 | Okenní otvor | NEW | 2.7 | 0.32 | 0.864 | 1.8 | 1.5
Okenní otvor | Půdorys 3.NP | Zateplovací systémy | 1652Okn0798426589 | m3 | Okenní otvor | NEW | 2.7 | 0.32 | 0.864 | 1.8 | 1.5
Okenní otvor | Půdorys 3.NP | Zateplovací systémy | 1652Okn0798426573 | m3 | Okenní otvor | NEW | 2.16 | 0.32 | 0.691 | 1.8 | 1.2
Okenní otvor | Půdorys 3.NP | Zateplovací systémy | 1652Okn0798426576 | m3 | Okenní otvor | NEW | 2.16 | 0.32 | 0.691 | 1.8 | 1.2
Okenní otvor | Půdorys 3.NP | Zateplovací systémy | 1652Okn0798426579 | m3 | Okenní otvor | NEW | 2.16 | 0.32 | 0.691 | 1.8 | 1.2
Okenní otvor | Půdorys 3.NP | Zateplovací systémy | 1652Okn0798426569 | m3 | Okenní otvor | NEW | 2.16 | 0.32 | 0.691 | 1.8 | 1.2
Okenní otvor | Půdorys 3.NP | Zateplovací systémy | 1652Okn0798440651 | m3 | Okenní otvor | NEW | 0.49 | 0.125 | 0.061 | 0.7 | 0.7
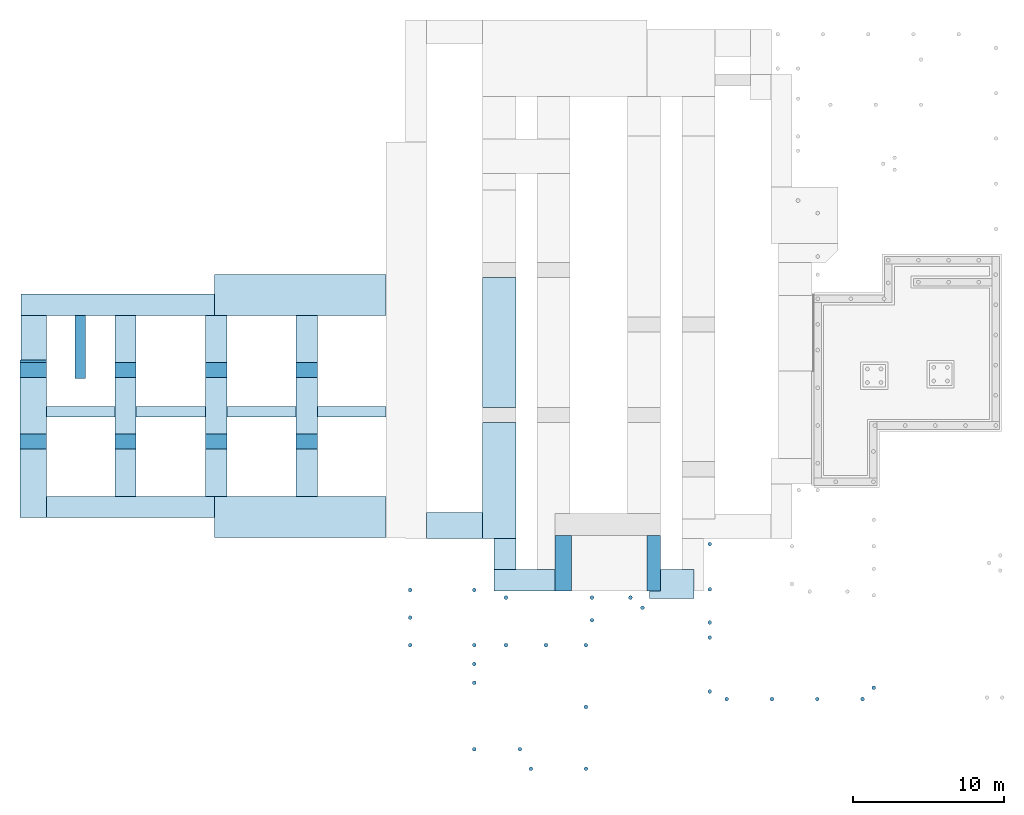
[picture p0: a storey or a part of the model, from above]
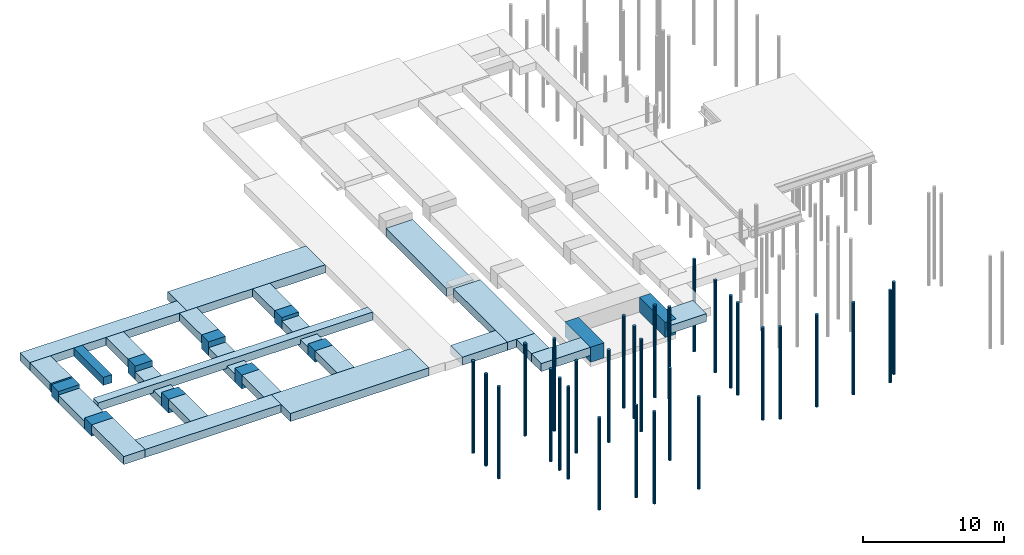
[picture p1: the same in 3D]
Properties of the parts of a building model (IFC4), part 19 of 45

# IfcOpeningElement: Opening (1638)
Name | In | Object Layer Attributes #1, Práce | Object Layer Attributes #1, Allright_Stavebni_dil_ID | Object Layer Attributes #1, Jednotka | Object Layer Attributes #1, Název_objektu | Status | Area (m2) | Depth (m) | Volume (m3) | Height (m) | Width (m)
Dveřní otvor | Půdorys 3.NP | Betonářské práce | 1652Dve0798428303 | m3 | Dveřní otvor | NEW | 3.131 | 0.125 | 0.391 | 2.02 | 1.55 | NEMSOK - Object Layer Attributes #1, Směr otevírání dveří: -
Dveřní otvor | Půdorys 3.NP | Betonářské práce | 1652Dve0798437612 | m3 | Dveřní otvor | NEW | 3.131 | 0.125 | 0.391 | 2.02 | 1.55 | NEMSOK - Object Layer Attributes #1, Směr otevírání dveří: -
Dveřní otvor | Půdorys 3.NP | Betonářské práce | 1652Dve0798439856 | m3 | Dveřní otvor | NEW | 2.424 | 0.125 | 0.303 | 2.02 | 1.2 | NEMSOK - Object Layer Attributes #1, Směr otevírání dveří: L
Okenní otvor | Půdorys 3.NP | Zateplovací systémy | 1652Okn0798430318 | m3 | Okenní otvor | NEW | 4.2 | 0.32 | 1.344 | 1.75 | 2.4
Okenní otvor | Půdorys 3.NP | Zateplovací systémy | 1652Okn0798430312 | m3 | Okenní otvor | NEW | 4.95 | 0.32 | 1.584 | 2.75 | 1.8
Okenní otvor | Půdorys 3.NP | Zateplovací systémy | 1652Okn0798430273 | m3 | Okenní otvor | NEW | 9.9 | 0.32 | 3.168 | 2.75 | 3.6
Okenní otvor | Půdorys 3.NP | Zateplovací systémy | 1652Okn0798426749 | m3 | Okenní otvor | NEW | 4.95 | 0.32 | 1.584 | 2.75 | 1.8
Okenní otvor | Půdorys 3.NP | Zateplovací systémy | 1652Okn0798426751 | m3 | Okenní otvor | NEW | 5.6 | 0.32 | 1.792 | 1.75 | 3.2
Okenní otvor | Půdorys 3.NP | Zateplovací systémy | 1652Okn0798442795 | m3 | Okenní otvor | NEW | 0.72 | 0.125 | 0.09 | 1.2 | 0.6
Okenní otvor | Půdorys 3.NP | Zateplovací systémy | 1652Okn0798426543 | m2 | Okenní otvor | NEW | 0.15 | 0.4 | 0.015 | 0.1 | 1.5 | NEMSOK - Object Layer Attributes #2, Status: Nový; Object Layer Attributes #2, Práce: Zateplovací systémy; Object Layer Attributes #2, Allright_Stavebni_dil_ID: 1652Okn0798443089; Object Layer Attributes #2, Jednotka: m3; Object Layer Attributes #2, Název_objektu: Okenní otvor
Okenní otvor | Půdorys 3.NP | Zateplovací systémy | 1652Okn0798426541 | m2 | Okenní otvor | NEW | 3 | 0.4 | 0.3 | 2 | 1.5 | NEMSOK - Object Layer Attributes #2, Status: Nový; Object Layer Attributes #2, Práce: Zateplovací systémy; Object Layer Attributes #2, Allright_Stavebni_dil_ID: 1652Okn0798443093; Object Layer Attributes #2, Jednotka: m3; Object Layer Attributes #2, Název_objektu: Okenní otvor
Okenní otvor | Půdorys 3.NP | Zateplovací systémy | 1652Okn0798444230 | m2 | Okenní otvor | NEW | 2.7 | 0.4 | 0.27 | 1.8 | 1.5 | NEMSOK - Object Layer Attributes #2, Status: Nový; Object Layer Attributes #2, Práce: Zateplovací systémy; Object Layer Attributes #2, Allright_Stavebni_dil_ID: 1652Okn0798444231; Object Layer Attributes #2, Jednotka: m3; Object Layer Attributes #2, Název_objektu: Okenní otvor
Dveřní otvor | Půdorys 3.NP | Betonářské práce | 1652Dve0798444788 | m3 | Dveřní otvor | NEW | 2.691 | 0.5 | 1.346 | 2.07 | 1.3 | NEMSOK - Object Layer Attributes #1, Směr otevírání dveří: -
Dveřní otvor | Půdorys 3.NP | Betonářské práce | 1652Dve0798444787 | m3 | Dveřní otvor | NEW | 2.691 | 0.5 | 1.346 | 2.07 | 1.3 | NEMSOK - Object Layer Attributes #1, Směr otevírání dveří: -
Dveřní otvor | Půdorys 3.NP | Betonářské práce | 1652Dve0798444997 | m3 | Dveřní otvor | NEW | 3.63 | 0.5 | 1.815 | 2.2 | 1.65 | NEMSOK - Object Layer Attributes #1, Směr otevírání dveří: -
Okenní otvor | Půdorys 3.NP | Zateplovací systémy | 1652Okn0798442357 | m3 | Okenní otvor | NEW | 6.281 | 0.3 | 1.884 | 3.35 | 1.875
Prostup stěnou | Půdorys 3.NP | Betonářské práce | 1652SVý0798447123 | m3 | Stěnový výklenek | NEW | 0.023 | 0.32 | 0.007 | 0.15 | 0.15
Prostup stěnou | Půdorys 3.NP | Betonářské práce | 1652SVý0798447132 | m3 | Stěnový výklenek | NEW | 0.023 | 0.32 | 0.007 | 0.15 | 0.15
Prostup stěnou | Půdorys 3.NP | Betonářské práce | 1652SVý0798447138 | m3 | Stěnový výklenek | NEW | 0.023 | 0.32 | 0.007 | 0.15 | 0.15
Prostup stěnou | Půdorys 3.NP | Betonářské práce | 1652SVý0798447144 | m3 | Stěnový výklenek | NEW | 0.023 | 0.32 | 0.007 | 0.15 | 0.15
Prostup stěnou | Půdorys 3.NP | Betonářské práce | 1652SVý0798447150 | m3 | Stěnový výklenek | NEW | 0.023 | 0.32 | 0.007 | 0.15 | 0.15
Prostup stěnou | Půdorys 3.NP | Betonářské práce | 1652SVý0798447172 | m3 | Stěnový výklenek | NEW | 0.023 | 0.32 | 0.007 | 0.15 | 0.15
Prostup stěnou | Půdorys 3.NP | Betonářské práce | 1652SVý0798447170 | m3 | Stěnový výklenek | NEW | 0.023 | 0.32 | 0.007 | 0.15 | 0.15
Prostup stěnou | Půdorys 3.NP | Betonářské práce | 1652SVý0798447168 | m3 | Stěnový výklenek | NEW | 0.023 | 0.32 | 0.007 | 0.15 | 0.15
Prostup stěnou | Půdorys 3.NP | Betonářské práce | 1652SVý0798447166 | m3 | Stěnový výklenek | NEW | 0.023 | 0.32 | 0.007 | 0.15 | 0.15
Prostup stěnou | Půdorys 3.NP | Betonářské práce | 1652SVý0798447164 | m3 | Stěnový výklenek | NEW | 0.023 | 0.32 | 0.007 | 0.15 | 0.15
Prostup stěnou | Půdorys 3.NP | Betonářské práce | 1652SVý0798447212 | m3 | Stěnový výklenek | NEW | 0.023 | 0.32 | 0.007 | 0.15 | 0.15
Prostup stěnou | Půdorys 3.NP | Betonářské práce | 1652SVý0798447211 | m3 | Stěnový výklenek | NEW | 0.023 | 0.32 | 0.007 | 0.15 | 0.15
Prostup stěnou | Půdorys 3.NP | Betonářské práce | 1652SVý0798447210 | m3 | Stěnový výklenek | NEW | 0.023 | 0.32 | 0.007 | 0.15 | 0.15
Prostup stěnou | Půdorys 3.NP | Betonářské práce | 1652SVý0798447209 | m3 | Stěnový výklenek | NEW | 0.023 | 0.32 | 0.007 | 0.15 | 0.15
Prostup stěnou | Půdorys 3.NP | Betonářské práce | 1652SVý0798447208 | m3 | Stěnový výklenek | NEW | 0.023 | 0.32 | 0.007 | 0.15 | 0.15
Prostup stěnou | Půdorys 3.NP | Betonářské práce | 1652SVý0798447234 | m3 | Stěnový výklenek | NEW | 0.023 | 0.32 | 0.007 | 0.15 | 0.15
Prostup stěnou | Půdorys 3.NP | Betonářské práce | 1652SVý0798447233 | m3 | Stěnový výklenek | NEW | 0.023 | 0.32 | 0.007 | 0.15 | 0.15
Prostup stěnou | Půdorys 3.NP | Betonářské práce | 1652SVý0798447232 | m3 | Stěnový výklenek | NEW | 0.023 | 0.32 | 0.007 | 0.15 | 0.15
Prostup stěnou | Půdorys 3.NP | Betonářské práce | 1652SVý0798447231 | m3 | Stěnový výklenek | NEW | 0.023 | 0.32 | 0.007 | 0.15 | 0.15
Prostup stěnou | Půdorys 3.NP | Betonářské práce | 1652SVý0798447230 | m3 | Stěnový výklenek | NEW | 0.023 | 0.32 | 0.007 | 0.15 | 0.15
Prostup stěnou | Půdorys 3.NP | Betonářské práce | 1652SVý0798447262 | m3 | Stěnový výklenek | NEW | 0.023 | 0.32 | 0.007 | 0.15 | 0.15
Prostup stěnou | Půdorys 3.NP | Betonářské práce | 1652SVý0798447261 | m3 | Stěnový výklenek | NEW | 0.023 | 0.32 | 0.007 | 0.15 | 0.15
Prostup stěnou | Půdorys 3.NP | Betonářské práce | 1652SVý0798447260 | m3 | Stěnový výklenek | NEW | 0.023 | 0.32 | 0.007 | 0.15 | 0.15
Prostup stěnou | Půdorys 3.NP | Betonářské práce | 1652SVý0798447259 | m3 | Stěnový výklenek | NEW | 0.023 | 0.32 | 0.007 | 0.15 | 0.15
Prostup stěnou | Půdorys 3.NP | Betonářské práce | 1652SVý0798447258 | m3 | Stěnový výklenek | NEW | 0.023 | 0.32 | 0.007 | 0.15 | 0.15
Prostup stěnou | Půdorys 3.NP | Betonářské práce | 1652SVý0798447310 | m3 | Stěnový výklenek | NEW | 0.023 | 0.32 | 0.007 | 0.15 | 0.15
Prostup stěnou | Půdorys 3.NP | Betonářské práce | 1652SVý0798447309 | m3 | Stěnový výklenek | NEW | 0.023 | 0.32 | 0.007 | 0.15 | 0.15
Prostup stěnou | Půdorys 3.NP | Betonářské práce | 1652SVý0798447308 | m3 | Stěnový výklenek | NEW | 0.023 | 0.32 | 0.007 | 0.15 | 0.15
Prostup stěnou | Půdorys 3.NP | Betonářské práce | 1652SVý0798447307 | m3 | Stěnový výklenek | NEW | 0.023 | 0.32 | 0.007 | 0.15 | 0.15
Prostup stěnou | Půdorys 3.NP | Betonářské práce | 1652SVý0798447306 | m3 | Stěnový výklenek | NEW | 0.023 | 0.32 | 0.007 | 0.15 | 0.15
Prostup stěnou | Půdorys 3.NP | Betonářské práce | 1652SVý0798447334 | m3 | Stěnový výklenek | NEW | 0.023 | 0.32 | 0.007 | 0.15 | 0.15
Prostup stěnou | Půdorys 3.NP | Betonářské práce | 1652SVý0798447333 | m3 | Stěnový výklenek | NEW | 0.023 | 0.32 | 0.007 | 0.15 | 0.15
Prostup stěnou | Půdorys 3.NP | Betonářské práce | 1652SVý0798447332 | m3 | Stěnový výklenek | NEW | 0.023 | 0.32 | 0.007 | 0.15 | 0.15
Prostup stěnou | Půdorys 3.NP | Betonářské práce | 1652SVý0798447331 | m3 | Stěnový výklenek | NEW | 0.023 | 0.32 | 0.007 | 0.15 | 0.15
Prostup stěnou | Půdorys 3.NP | Betonářské práce | 1652SVý0798447330 | m3 | Stěnový výklenek | NEW | 0.023 | 0.32 | 0.007 | 0.15 | 0.15
Prostup stěnou | Půdorys 3.NP | Betonářské práce | 1652SVý0798447360 | m3 | Stěnový výklenek | NEW | 0.023 | 0.32 | 0.007 | 0.15 | 0.15
Prostup stěnou | Půdorys 3.NP | Betonářské práce | 1652SVý0798447359 | m3 | Stěnový výklenek | NEW | 0.023 | 0.32 | 0.007 | 0.15 | 0.15
Prostup stěnou | Půdorys 3.NP | Betonářské práce | 1652SVý0798447358 | m3 | Stěnový výklenek | NEW | 0.023 | 0.32 | 0.007 | 0.15 | 0.15
Prostup stěnou | Půdorys 3.NP | Betonářské práce | 1652SVý0798447357 | m3 | Stěnový výklenek | NEW | 0.023 | 0.32 | 0.007 | 0.15 | 0.15
Prostup stěnou | Půdorys 3.NP | Betonářské práce | 1652SVý0798447356 | m3 | Stěnový výklenek | NEW | 0.023 | 0.32 | 0.007 | 0.15 | 0.15
Okenní otvor | Půdorys 3.NP | Zateplovací systémy | 1652Okn0000000194 | m2 | Okenní otvor | NEW | 3.48 | 0.6 | 0.348 | 1.45 | 2.4 | NEMSOK - Object Layer Attributes #2, Status: Nový; Object Layer Attributes #2, Práce: Zateplovací systémy; Object Layer Attributes #2, Allright_Stavebni_dil_ID: 1652Okn0798445214; Object Layer Attributes #2, Jednotka: m3; Object Layer Attributes #2, Název_objektu: Okenní otvor
Prostup deskou | Půdorys 3.NP | Betonářské práce | 1654DOt0000000474 | m3 | Otvor v desce | NEW | 0.1 | 0.5 | 0.025 | 0.25 | 0.2
Prostup deskou | Půdorys 3.NP | Betonářské práce | 1654DOt0000000476 | m3 | Otvor v desce | NEW | 0.385 | 0.7 | 0.096 | 0.25 | 0.55
Prostup deskou | Půdorys 3.NP | Betonářské práce | 1654DOt0000000517 | m3 | Otvor v desce | NEW | 0.4 | 0.8 | 0.1 | 0.25 | 0.5
Prostup deskou | Půdorys 3.NP | Betonářské práce | 1654DOt0000000521 | m3 | Otvor v desce | NEW | 0.38 | 0.4 | 0.095 | 0.25 | 0.95
Prostup deskou | Půdorys 3.NP | Betonářské práce | 1654DOt0000000523 | m3 | Otvor v desce | NEW | 0.495 | 0.9 | 0.124 | 0.25 | 0.55
Prostup deskou | Půdorys 3.NP | Betonářské práce | 1654DOt0000000534 | m3 | Otvor v desce | NEW | 0.33 | 0.6 | 0.082 | 0.25 | 0.55
Prostup deskou | Půdorys 3.NP | Betonářské práce | 1654DOt0000000536 | m3 | Otvor v desce | NEW | 0.35 | 0.7 | 0.087 | 0.25 | 0.5
Prostup deskou | Půdorys 3.NP | Betonářské práce | 1654DOt0000001018 | m3 | Otvor v desce | NEW | 0.096 | 0.275 | 0.024 | 0.25 | 0.35
Prostup deskou | Půdorys 3.NP | Betonářské práce | 1654DOt0000000532 | m3 | Otvor v desce | NEW | 0.36 | 0.6 | 0.09 | 0.25 | 0.6
Prostup deskou | Půdorys 3.NP | Betonářské práce | 1654DOt0000001230 | m3 | Otvor v desce | NEW | 0.01 | 0.1 | 0.002 | 0.2 | 0.1
Prostup deskou | Půdorys 3.NP | Betonářské práce | 1654DOt0000001213 | m3 | Otvor v desce | NEW | 0.07 | 0.2 | 0.014 | 0.2 | 0.35
Prostup deskou | Půdorys 3.NP | Betonářské práce | 1654DOt0000000546 | m3 | Otvor v desce | NEW | 0.1 | 0.5 | 0.025 | 0.25 | 0.2
Prostup deskou | Půdorys 3.NP | Betonářské práce | 1654DOt0000000552 | m3 | Otvor v desce | NEW | 0.385 | 0.7 | 0.096 | 0.25 | 0.55
Prostup deskou | Půdorys 3.NP | Betonářské práce | 1654DOt0000000554 | m3 | Otvor v desce | NEW | 0.14 | 0.7 | 0.035 | 0.25 | 0.2
Prostup deskou | Půdorys 3.NP | Betonářské práce | 1654DOt0000000550 | m3 | Otvor v desce | NEW | 3.705 | 1.3 | 0.926 | 0.25 | 2.85
Prostup deskou | Půdorys 3.NP | Betonářské práce | 1654DOt0000000548 | m3 | Otvor v desce | NEW | 0.26 | 1.3 | 0.065 | 0.25 | 0.2
Prostup deskou | Půdorys 3.NP | Betonářské práce | 1654DOt0000000570 | m3 | Otvor v desce | NEW | 0.3 | 0.6 | 0.075 | 0.25 | 0.5
Prostup deskou | Půdorys 3.NP | Betonářské práce | 1654DOt0000000568 | m3 | Otvor v desce | NEW | 0.45 | 0.3 | 0.112 | 0.25 | 1.5
Prostup deskou | Půdorys 3.NP | Betonářské práce | 1654DOt0000000504 | m3 | Otvor v desce | NEW | 0.2 | 0.5 | 0.05 | 0.25 | 0.4
Prostup deskou | Půdorys 3.NP | Betonářské práce | 1654DOt0000000506 | m3 | Otvor v desce | NEW | 0.25 | 0.5 | 0.062 | 0.25 | 0.5
Prostup deskou | Půdorys 3.NP | Betonářské práce | 1654DOt0000000478 | m3 | Otvor v desce | NEW | 0.81 | 2.7 | 0.203 | 0.25 | 0.3
Okenní otvor | Půdorys 4.NP | Zateplovací systémy | 1752Okn0000010346 | m3 | Okenní otvor | NEW | 2.775 | 0.32 | 0.888 | 1.85 | 1.5
Okenní otvor | Půdorys 4.NP | Zateplovací systémy | 1752Okn0000010129 | m3 | Okenní otvor | NEW | 2.775 | 0.32 | 0.888 | 1.85 | 1.5
Okenní otvor | Půdorys 4.NP | Zateplovací systémy | 1752Okn0000010137 | m3 | Okenní otvor | NEW | 2.775 | 0.32 | 0.888 | 1.85 | 1.5
Okenní otvor | Půdorys 4.NP | Zateplovací systémy | 1752Okn0000010333 | m3 | Okenní otvor | NEW | 2.7 | 0.32 | 0.864 | 1.8 | 1.5
Okenní otvor | Půdorys 4.NP | Zateplovací systémy | 1752Okn0000010413 | m3 | Okenní otvor | NEW | 2.7 | 0.32 | 0.864 | 1.8 | 1.5
Okenní otvor | Půdorys 4.NP | Zateplovací systémy | 1752Okn0000010419 | m3 | Okenní otvor | NEW | 2.7 | 0.32 | 0.864 | 1.8 | 1.5
Dveřní otvor | Půdorys 4.NP | Betonářské práce | 1752Dve0000010406 | m3 | Dveřní otvor | NEW | 2.475 | 0.32 | 0.792 | 2.75 | 0.9 | NEMSOK - Object Layer Attributes #1, Směr otevírání dveří: P
Okenní otvor | Půdorys 4.NP | Zateplovací systémy | 1752Okn0000010403 | m3 | Okenní otvor | NEW | 2.7 | 0.32 | 0.864 | 1.8 | 1.5
Okenní otvor | Půdorys 4.NP | Zateplovací systémy | 1752Okn0000010408 | m3 | Okenní otvor | NEW | 2.7 | 0.32 | 0.864 | 1.8 | 1.5
Dveřní otvor | Půdorys 4.NP | Betonářské práce | 1752Dve0000010411 | m3 | Dveřní otvor | NEW | 2.475 | 0.32 | 0.792 | 2.75 | 0.9 | NEMSOK - Object Layer Attributes #1, Směr otevírání dveří: L
Okenní otvor | Půdorys 4.NP | Zateplovací systémy | 1752Okn0000010416 | m3 | Okenní otvor | NEW | 2.7 | 0.32 | 0.864 | 1.8 | 1.5
Dveřní otvor | Půdorys 4.NP | Betonářské práce | 1752Dve0000012647 | m3 | Dveřní otvor | NEW | 3.503 | 0.25 | 0.876 | 2.26 | 1.55 | NEMSOK - Object Layer Attributes #1, Směr otevírání dveří: -
Dveřní otvor | Půdorys 4.NP | Betonářské práce | 1752Dve0000012645 | m3 | Dveřní otvor | NEW | 3.503 | 0.25 | 0.876 | 2.26 | 1.55 | NEMSOK - Object Layer Attributes #1, Směr otevírání dveří: -
Okenní otvor | Půdorys 4.NP | Zateplovací systémy | 1752Okn0000010245 | m3 | Okenní otvor | NEW | 2.7 | 0.3 | 0.81 | 1.8 | 1.5
Okenní otvor | Půdorys 4.NP | Zateplovací systémy | 1752Okn0000010241 | m3 | Okenní otvor | NEW | 2.7 | 0.3 | 0.81 | 1.8 | 1.5
Okenní otvor | Půdorys 4.NP | Zateplovací systémy | 1752Okn0000010237 | m3 | Okenní otvor | NEW | 2.7 | 0.3 | 0.81 | 1.8 | 1.5
Dveřní otvor | Půdorys 4.NP | Betonářské práce | 1752Dve0000009933 | m3 | Dveřní otvor | NEW | 3.131 | 0.125 | 0.391 | 2.02 | 1.55 | NEMSOK - Object Layer Attributes #1, Směr otevírání dveří: -
Okenní otvor | Půdorys 4.NP | Zateplovací systémy | 1752Okn0798427730 | m3 | Okenní otvor | NEW | 0.49 | 0.125 | 0.061 | 0.7 | 0.7
Dveřní otvor | Půdorys 4.NP | Betonářské práce | 1752Dve0000019396 | m3 | Dveřní otvor | NEW | 2.02 | 0.1 | 0.202 | 2.02 | 1 | NEMSOK - Object Layer Attributes #1, Směr otevírání dveří: L
Dveřní otvor | Půdorys 4.NP | Betonářské práce | 1752Dve0000019362 | m3 | Dveřní otvor | NEW | 3.131 | 0.125 | 0.391 | 2.02 | 1.55 | NEMSOK - Object Layer Attributes #1, Směr otevírání dveří: -
Okenní otvor | Půdorys 4.NP | Zateplovací systémy | 1752Okn0000011298 | m3 | Okenní otvor | NEW | 5.263 | 0.32 | 1.684 | 2.77 | 1.9
Okenní otvor | Půdorys 4.NP | Zateplovací systémy | 1752Okn0000011290 | m3 | Okenní otvor | NEW | 2.493 | 0.32 | 0.798 | 2.77 | 0.9
Okenní otvor | Půdorys 4.NP | Zateplovací systémy | 1752Okn0000010563 | m3 | Okenní otvor | NEW | 6.371 | 0.32 | 2.039 | 2.77 | 2.3
Okenní otvor | Půdorys 4.NP | Zateplovací systémy | 1752Okn0000011206 | m3 | Okenní otvor | NEW | 2.493 | 0.32 | 0.798 | 2.77 | 0.9
Okenní otvor | Půdorys 4.NP | Zateplovací systémy | 1752Okn0000010549 | m3 | Okenní otvor | NEW | 8.14 | 0.32 | 2.605 | 1.85 | 4.4
Okenní otvor | Půdorys 4.NP | Zateplovací systémy | 1752Okn0000011355 | m3 | Okenní otvor | NEW | 4.44 | 0.32 | 1.421 | 1.85 | 2.4
Dveřní otvor | Půdorys 4.NP | Betonářské práce | 1752Dve0798427807 | m3 | Dveřní otvor | NEW | 1.818 | 0.125 | 0.227 | 2.02 | 0.9 | NEMSOK - Object Layer Attributes #1, Směr otevírání dveří: L
Okenní otvor | Půdorys 4.NP | Zateplovací systémy | 1752Okn0798429072 | m3 | Okenní otvor | NEW | 0.72 | 0.125 | 0.09 | 1.2 | 0.6
Okenní otvor | Půdorys 4.NP | Zateplovací systémy | 1752Okn0798429942 | m2 | Okenní otvor | NEW | 2.7 | 0.4 | 0.27 | 1.8 | 1.5 | NEMSOK - Object Layer Attributes #2, Status: Nový; Object Layer Attributes #2, Práce: Zateplovací systémy; Object Layer Attributes #2, Allright_Stavebni_dil_ID: 1752Okn0798429941; Object Layer Attributes #2, Jednotka: m3; Object Layer Attributes #2, Název_objektu: Okenní otvor
Okenní otvor | Půdorys 4.NP | Zateplovací systémy | 1752Okn0000014299 | m2 | Okenní otvor | NEW | 2.25 | 0.4 | 0.225 | 1.5 | 1.5 | NEMSOK - Object Layer Attributes #2, Status: Nový; Object Layer Attributes #2, Práce: Zateplovací systémy; Object Layer Attributes #2, Allright_Stavebni_dil_ID: 1752Okn0798429296; Object Layer Attributes #2, Jednotka: m3; Object Layer Attributes #2, Název_objektu: Okenní otvor
Dveřní otvor | Půdorys 4.NP | Betonářské práce | 1752Dve0798427876 | m3 | Dveřní otvor | NEW | 2.424 | 0.125 | 0.303 | 2.02 | 1.2 | NEMSOK - Object Layer Attributes #1, Směr otevírání dveří: L
Okenní otvor | Půdorys 4.NP | Zateplovací systémy | 1752Okn0000004757 | m2 | Okenní otvor | NEW | 2.04 | 0.6 | 0.204 | 0.85 | 2.4 | NEMSOK - Object Layer Attributes #2, Status: Nový; Object Layer Attributes #2, Práce: Zateplovací systémy; Object Layer Attributes #2, Allright_Stavebni_dil_ID: 1752Okn0798430812; Object Layer Attributes #2, Jednotka: m3; Object Layer Attributes #2, Název_objektu: Okenní otvor
Okenní otvor | Půdorys 4.NP | Zateplovací systémy | 1752Okn0000004756 | m2 | Okenní otvor | NEW | 3.36 | 0.6 | 0.336 | 1.4 | 2.4 | NEMSOK - Object Layer Attributes #2, Status: Nový; Object Layer Attributes #2, Práce: Zateplovací systémy; Object Layer Attributes #2, Allright_Stavebni_dil_ID: 1752Okn0798430984; Object Layer Attributes #2, Jednotka: m3; Object Layer Attributes #2, Název_objektu: Okenní otvor
Okenní otvor | Půdorys 4.NP | Zateplovací systémy | 1752Okn0798428006 | m3 | Okenní otvor | NEW | 2.719 | 0.3 | 0.816 | 1.45 | 1.875
Okenní otvor | Půdorys 4.NP | Zateplovací systémy | 1752Okn0000010198 | m3 | Okenní otvor | NEW | 2.16 | 0.32 | 0.691 | 1.8 | 1.2
Okenní otvor | Půdorys 4.NP | Zateplovací systémy | 1752Okn0000010202 | m3 | Okenní otvor | NEW | 2.16 | 0.32 | 0.691 | 1.8 | 1.2
Okenní otvor | Půdorys 4.NP | Zateplovací systémy | 1752Okn0000010206 | m3 | Okenní otvor | NEW | 2.16 | 0.32 | 0.691 | 1.8 | 1.2
Okenní otvor | Půdorys 4.NP | Zateplovací systémy | 1752Okn0000010210 | m3 | Okenní otvor | NEW | 2.16 | 0.32 | 0.691 | 1.8 | 1.2
Okenní otvor | Půdorys 4.NP | Zateplovací systémy | 1752Okn0000010214 | m3 | Okenní otvor | NEW | 2.7 | 0.32 | 0.864 | 1.8 | 1.5
Okenní otvor | Půdorys 4.NP | Zateplovací systémy | 1752Okn0000010216 | m3 | Okenní otvor | NEW | 2.7 | 0.32 | 0.864 | 1.8 | 1.5
Okenní otvor | Půdorys 4.NP | Zateplovací systémy | 1752Okn0000010218 | m3 | Okenní otvor | NEW | 2.7 | 0.32 | 0.864 | 1.8 | 1.5
Okenní otvor | Půdorys 4.NP | Zateplovací systémy | 1752Okn0000010224 | m3 | Okenní otvor | NEW | 2.7 | 0.32 | 0.864 | 1.8 | 1.5
Okenní otvor | Půdorys 4.NP | Zateplovací systémy | 1752Okn0000010222 | m3 | Okenní otvor | NEW | 2.7 | 0.32 | 0.864 | 1.8 | 1.5
Okenní otvor | Půdorys 4.NP | Zateplovací systémy | 1752Okn0000010220 | m3 | Okenní otvor | NEW | 2.7 | 0.32 | 0.864 | 1.8 | 1.5
Okenní otvor | Půdorys 4.NP | Zateplovací systémy | 1752Okn0000010173 | m3 | Okenní otvor | NEW | 2.16 | 0.32 | 0.691 | 1.8 | 1.2
Okenní otvor | Půdorys 4.NP | Zateplovací systémy | 1752Okn0000010179 | m3 | Okenní otvor | NEW | 2.16 | 0.32 | 0.691 | 1.8 | 1.2
Okenní otvor | Půdorys 4.NP | Zateplovací systémy | 1752Okn0000010184 | m3 | Okenní otvor | NEW | 2.16 | 0.32 | 0.691 | 1.8 | 1.2
Okenní otvor | Půdorys 4.NP | Zateplovací systémy | 1752Okn0000010189 | m3 | Okenní otvor | NEW | 2.16 | 0.32 | 0.691 | 1.8 | 1.2
Prostup deskou | Půdorys 4.NP | Betonářské práce | 1754DOt0000001350 | m3 | Otvor v desce | NEW | 0.09 | 0.3 | 0.023 | 0.25 | 0.3
Prostup deskou | Půdorys 4.NP | Betonářské práce | 1754DOt0000001345 | m3 | Otvor v desce | NEW | 0.04 | 0.2 | 0.01 | 0.25 | 0.2
Prostup deskou | Půdorys 4.NP | Betonářské práce | 1754DOt0000001310 | m3 | Otvor v desce | NEW | 0.04 | 0.2 | 0.01 | 0.25 | 0.2
Prostup deskou | Půdorys 4.NP | Betonářské práce | 1754DOt0000001317 | m3 | Otvor v desce | NEW | 0.09 | 0.3 | 0.023 | 0.25 | 0.3
Prostup deskou | Půdorys 4.NP | Betonářské práce | 1754DOt0000001332 | m3 | Otvor v desce | NEW | 0.09 | 0.3 | 0.023 | 0.25 | 0.3
Prostup deskou | Půdorys 4.NP | Betonářské práce | 1754DOt0000000863 | m3 | Otvor v desce | NEW | 0.04 | 0.2 | 0.01 | 0.25 | 0.2
Prostup deskou | Půdorys 4.NP | Betonářské práce | 1754DOt0000002245 | m3 | Otvor v desce | NEW | 0.01 | 0.1 | 0.001 | 0.1 | 0.1
Prostup deskou | Půdorys 4.NP | Betonářské práce | 1754DOt0000000885 | m3 | Otvor v desce | NEW | 0.14 | 0.7 | 0.035 | 0.25 | 0.2
Prostup deskou | Půdorys 4.NP | Betonářské práce | 1754DOt0000000877 | m3 | Otvor v desce | NEW | 0.113 | 0.45 | 0.028 | 0.25 | 0.25
Prostup deskou | Půdorys 4.NP | Betonářské práce | 1754DOt0000000883 | m3 | Otvor v desce | NEW | 0.385 | 0.7 | 0.096 | 0.25 | 0.55
Prostup deskou | Půdorys 4.NP | Betonářské práce | 1754DOt0000001414 | m3 | Otvor v desce | NEW | 0.112 | 0.25 | 0.028 | 0.25 | 0.45
Prostup deskou | Půdorys 4.NP | Betonářské práce | 1754DOt0000000881 | m3 | Otvor v desce | NEW | 3.705 | 1.3 | 0.926 | 0.25 | 2.85
Prostup deskou | Půdorys 4.NP | Betonářské práce | 1754DOt0000000879 | m3 | Otvor v desce | NEW | 0.26 | 1.3 | 0.065 | 0.25 | 0.2
Prostup deskou | Půdorys 4.NP | Betonářské práce | 1754DOt0000001571 | m3 | Otvor v desce | NEW | 0.045 | 0.15 | 0.011 | 0.25 | 0.3
Prostup deskou | Půdorys 4.NP | Betonářské práce | 1754DOt0000001564 | m3 | Otvor v desce | NEW | 0.09 | 0.3 | 0.023 | 0.25 | 0.3
Prostup deskou | Půdorys 4.NP | Betonářské práce | 1754DOt0000000889 | m3 | Otvor v desce | NEW | 0.125 | 0.5 | 0.031 | 0.25 | 0.25
Prostup deskou | Půdorys 4.NP | Betonářské práce | 1754DOt0000001522 | m3 | Otvor v desce | NEW | 0.113 | 0.25 | 0.028 | 0.25 | 0.45
Prostup deskou | Půdorys 4.NP | Betonářské práce | 1754DOt0000000887 | m3 | Otvor v desce | NEW | 0.195 | 0.3 | 0.049 | 0.25 | 0.65
Prostup deskou | Půdorys 4.NP | Betonářské práce | 1754DOt0000000857 | m3 | Otvor v desce | NEW | 0.04 | 0.2 | 0.01 | 0.25 | 0.2
Prostup deskou | Půdorys 4.NP | Betonářské práce | 1754DOt0000000859 | m3 | Otvor v desce | NEW | 0.04 | 0.2 | 0.01 | 0.25 | 0.2
Prostup deskou | Půdorys 4.NP | Betonářské práce | 1754DOt0000002283 | m3 | Otvor v desce | NEW | 0.018 | 0.118 | 0.004 | 0.25 | 0.149
Prostup deskou | Půdorys 4.NP | Betonářské práce | 1754DOt0000002300 | m3 | Otvor v desce | NEW | 0.018 | 0.118 | 0.004 | 0.25 | 0.149
Prostup deskou | Půdorys 4.NP | Betonářské práce | 1754DOt0000002305 | m3 | Otvor v desce | NEW | 0.018 | 0.118 | 0.004 | 0.25 | 0.149
Prostup deskou | Půdorys 4.NP | Betonářské práce | 1754DOt0000002310 | m3 | Otvor v desce | NEW | 0.018 | 0.118 | 0.004 | 0.25 | 0.149
Prostup deskou | Půdorys 4.NP | Betonářské práce | 1754DOt0000001296 | m3 | Otvor v desce | NEW | 0.04 | 0.2 | 0.01 | 0.25 | 0.2
Prostup deskou | Půdorys 4.NP | Betonářské práce | 1754DOt0000000869 | m3 | Otvor v desce | NEW | 0.09 | 0.3 | 0.023 | 0.25 | 0.3
Prostup deskou | Půdorys 4.NP | Betonářské práce | 1754DOt0000001175 | m3 | Otvor v desce | NEW | 0.09 | 0.3 | 0.023 | 0.25 | 0.3
Prostup deskou | Půdorys 4.NP | Betonářské práce | 1754DOt0000000867 | m3 | Otvor v desce | NEW | 0.09 | 0.3 | 0.023 | 0.25 | 0.3
Prostup deskou | Půdorys 4.NP | Betonářské práce | 1754DOt0000000871 | m3 | Otvor v desce | NEW | 0.04 | 0.2 | 0.01 | 0.25 | 0.2
Prostup deskou | Půdorys 4.NP | Betonářské práce | 1754DOt0000001262 | m3 | Otvor v desce | NEW | 0.09 | 0.3 | 0.023 | 0.25 | 0.3
Prostup deskou | Půdorys 4.NP | Betonářské práce | 1754DOt0000000865 | m3 | Otvor v desce | NEW | 0.09 | 0.3 | 0.023 | 0.25 | 0.3
Prostup deskou | Půdorys 4.NP | Betonářské práce | 1754DOt0000001099 | m3 | Otvor v desce | NEW | 0.09 | 0.3 | 0.023 | 0.25 | 0.3
Prostup deskou | Půdorys 4.NP | Betonářské práce | 1754DOt0000000861 | m3 | Otvor v desce | NEW | 0.09 | 0.3 | 0.023 | 0.25 | 0.3
Prostup deskou | Půdorys 4.NP | Betonářské práce | 1754DOt0000002355 | m3 | Otvor v desce | NEW | 0.09 | 0.3 | 0.023 | 0.25 | 0.3
Dveřní otvor | Půdorys 5.NP | Betonářské práce | 1852Dve0798427913 | m3 | Dveřní otvor | NEW | 3.131 | 0.125 | 0.391 | 2.02 | 1.55 | NEMSOK - Object Layer Attributes #1, Směr otevírání dveří: -
Dveřní otvor | Půdorys 5.NP | Betonářské práce | 1852Dve0000011172 | m3 | Dveřní otvor | NEW | 1.818 | 0.125 | 0.227 | 2.02 | 0.9 | NEMSOK - Object Layer Attributes #1, Směr otevírání dveří: L
Prostup stěnou | Půdorys 5.NP | Zateplovací systémy | 1852SVý0798426892 | m2 | Stěnový výklenek | NEW | 0.54 | 0.35 | 0.027 | 0.9 | 0.6 | NEMSOK - Object Layer Attributes #2, Status: Nový; Object Layer Attributes #2, Práce: Zednické práce; Object Layer Attributes #2, Allright_Stavebni_dil_ID: 1852SVý0798430541; Object Layer Attributes #2, Jednotka: m3; Object Layer Attributes #2, Název_objektu: Stěnový výklenek
Prostup stěnou | Půdorys 5.NP | Zateplovací systémy | 1852SVý0798426885 | m2 | Stěnový výklenek | NEW | 0.54 | 0.35 | 0.027 | 0.9 | 0.6 | NEMSOK - Object Layer Attributes #2, Status: Nový; Object Layer Attributes #2, Práce: Zednické práce; Object Layer Attributes #2, Allright_Stavebni_dil_ID: 1852SVý0798430544; Object Layer Attributes #2, Jednotka: m3; Object Layer Attributes #2, Název_objektu: Stěnový výklenek
Prostup stěnou | Půdorys 5.NP | Zateplovací systémy | 1852SVý0798426878 | m2 | Stěnový výklenek | NEW | 0.54 | 0.35 | 0.027 | 0.9 | 0.6 | NEMSOK - Object Layer Attributes #2, Status: Nový; Object Layer Attributes #2, Práce: Zednické práce; Object Layer Attributes #2, Allright_Stavebni_dil_ID: 1852SVý0798430547; Object Layer Attributes #2, Jednotka: m3; Object Layer Attributes #2, Název_objektu: Stěnový výklenek
Prostup stěnou | Půdorys 5.NP | Zateplovací systémy | 1852SVý0798426870 | m2 | Stěnový výklenek | NEW | 0.54 | 0.35 | 0.027 | 0.9 | 0.6 | NEMSOK - Object Layer Attributes #2, Status: Nový; Object Layer Attributes #2, Práce: Zednické práce; Object Layer Attributes #2, Allright_Stavebni_dil_ID: 1852SVý0798430550; Object Layer Attributes #2, Jednotka: m3; Object Layer Attributes #2, Název_objektu: Stěnový výklenek
Prostup stěnou | Půdorys 5.NP | Zateplovací systémy | 1852SVý0798426862 | m2 | Stěnový výklenek | NEW | 0.54 | 0.35 | 0.027 | 0.9 | 0.6 | NEMSOK - Object Layer Attributes #2, Status: Nový; Object Layer Attributes #2, Práce: Zednické práce; Object Layer Attributes #2, Allright_Stavebni_dil_ID: 1852SVý0798430553; Object Layer Attributes #2, Jednotka: m3; Object Layer Attributes #2, Název_objektu: Stěnový výklenek
Prostup stěnou | Půdorys 5.NP | Zateplovací systémy | 1852SVý0798426898 | m2 | Stěnový výklenek | NEW | 0.54 | 0.35 | 0.027 | 0.9 | 0.6 | NEMSOK - Object Layer Attributes #2, Status: Nový; Object Layer Attributes #2, Práce: Zednické práce; Object Layer Attributes #2, Allright_Stavebni_dil_ID: 1852SVý0798430538; Object Layer Attributes #2, Jednotka: m3; Object Layer Attributes #2, Název_objektu: Stěnový výklenek
Prostup stěnou | Půdorys 5.NP | Zateplovací systémy | 1852SVý0798427025 | m2 | Stěnový výklenek | NEW | 0.76 | 0.35 | 0.038 | 0.8 | 0.95 | NEMSOK - Object Layer Attributes #2, Status: Nový; Object Layer Attributes #2, Práce: Zednické práce; Object Layer Attributes #2, Allright_Stavebni_dil_ID: 1852SVý0798430726; Object Layer Attributes #2, Jednotka: m3; Object Layer Attributes #2, Název_objektu: Stěnový výklenek
Prostup stěnou | Půdorys 5.NP | Zateplovací systémy | 1852SVý0798426977 | m2 | Stěnový výklenek | NEW | 1.17 | 0.35 | 0.059 | 0.9 | 1.3 | NEMSOK - Object Layer Attributes #2, Status: Nový; Object Layer Attributes #2, Práce: Zednické práce; Object Layer Attributes #2, Allright_Stavebni_dil_ID: 1852SVý0798430723; Object Layer Attributes #2, Jednotka: m3; Object Layer Attributes #2, Název_objektu: Stěnový výklenek
Prostup stěnou | Půdorys 5.NP | Zateplovací systémy | 1852SVý0798427000 | m2 | Stěnový výklenek | NEW | 0.76 | 0.35 | 0.038 | 0.8 | 0.95 | NEMSOK - Object Layer Attributes #2, Status: Nový; Object Layer Attributes #2, Práce: Zednické práce; Object Layer Attributes #2, Allright_Stavebni_dil_ID: 1852SVý0798430720; Object Layer Attributes #2, Jednotka: m3; Object Layer Attributes #2, Název_objektu: Stěnový výklenek
Prostup stěnou | Půdorys 5.NP | Zateplovací systémy | 1852SVý0798426936 | m2 | Stěnový výklenek | NEW | 0.225 | 0.35 | 0.011 | 0.45 | 0.5 | NEMSOK - Object Layer Attributes #2, Status: Nový; Object Layer Attributes #2, Práce: Zednické práce; Object Layer Attributes #2, Allright_Stavebni_dil_ID: 1852SVý0798430717; Object Layer Attributes #2, Jednotka: m3; Object Layer Attributes #2, Název_objektu: Stěnový výklenek
Dveřní otvor | Půdorys 5.NP | Betonářské práce | 1852Dve0798427752 | m2 | Dveřní otvor | NEW | 1.66 | 0.35 | 0.083 | 2 | 0.83 | NEMSOK - Object Layer Attributes #1, Směr otevírání dveří: L; Object Layer Attributes #2, Status: Nový; Object Layer Attributes #2, Práce: Betonářské práce; Object Layer Attributes #2, Allright_Stavebni_dil_ID: 1852Dve0798431140; Object Layer Attributes #2, Jednotka: m3; Object Layer Attributes #2, Název_objektu: Dveřní otvor; Object Layer Attributes #2, Směr otevírání dveří: L
Okenní otvor | Půdorys 5.NP | Zateplovací systémy | 1852Okn0798433060 | m2 | Okenní otvor | NEW | 1.35 | 0.45 | 0.202 | 1.5 | 0.9 | NEMSOK - Object Layer Attributes #2, Status: Nový; Object Layer Attributes #2, Práce: Zateplovací systémy; Object Layer Attributes #2, Allright_Stavebni_dil_ID: 1852Okn0798433059; Object Layer Attributes #2, Jednotka: m3; Object Layer Attributes #2, Název_objektu: Okenní otvor
Okenní otvor | Půdorys 5.NP | Zateplovací systémy | 1852Okn0798426633 | m2 | Okenní otvor | NEW | 1.35 | 0.65 | 0.202 | 1.5 | 0.9 | NEMSOK - Object Layer Attributes #2, Status: Nový; Object Layer Attributes #2, Práce: Zateplovací systémy; Object Layer Attributes #2, Allright_Stavebni_dil_ID: 1852Okn0798431425; Object Layer Attributes #2, Jednotka: m3; Object Layer Attributes #2, Název_objektu: Okenní otvor
Okenní otvor | Půdorys 5.NP | Zateplovací systémy | 1852Okn0798426741 | m2 | Okenní otvor | NEW | 0.81 | 0.65 | 0.122 | 0.9 | 0.9 | NEMSOK - Object Layer Attributes #2, Status: Nový; Object Layer Attributes #2, Práce: Zateplovací systémy; Object Layer Attributes #2, Allright_Stavebni_dil_ID: 1852Okn0798431466; Object Layer Attributes #2, Jednotka: m3; Object Layer Attributes #2, Název_objektu: Okenní otvor
Prostup stěnou | Půdorys 5.NP | Zateplovací systémy | 1852SVý0798431023 | m2 | Stěnový výklenek | NEW | 0.3 | 0.4 | 0.03 | 0.5 | 0.6 | NEMSOK - Object Layer Attributes #2, Status: Nový; Object Layer Attributes #2, Práce: Zednické práce; Object Layer Attributes #2, Allright_Stavebni_dil_ID: 1852SVý0798431024; Object Layer Attributes #2, Jednotka: m3; Object Layer Attributes #2, Název_objektu: Stěnový výklenek
Okenní otvor | Půdorys 5.NP | Zateplovací systémy | 1852Okn0000006103 | m2 | Okenní otvor | NEW | 9.6 | 0.6 | 0.96 | 4 | 2.4 | NEMSOK - Object Layer Attributes #2, Status: Nový; Object Layer Attributes #2, Práce: Zateplovací systémy; Object Layer Attributes #2, Allright_Stavebni_dil_ID: 1852Okn0798433632; Object Layer Attributes #2, Jednotka: m3; Object Layer Attributes #2, Název_objektu: Okenní otvor
Dveřní otvor | Půdorys 5.NP | Betonářské práce | 1852Dve0798434465 | m3 | Dveřní otvor | NEW | 2.691 | 0.5 | 1.346 | 2.07 | 1.3 | NEMSOK - Object Layer Attributes #1, Směr otevírání dveří: -
Dveřní otvor | Půdorys 5.NP | Betonářské práce | 1852Dve0798434464 | m3 | Dveřní otvor | NEW | 2.691 | 0.5 | 1.346 | 2.07 | 1.3 | NEMSOK - Object Layer Attributes #1, Směr otevírání dveří: -
Dveřní otvor | Půdorys 5.NP | Betonářské práce | 1852Dve0000002915 | m2 | Dveřní otvor | NEW | 7.2 | 0.6 | 0.72 | 3 | 2.4 | NEMSOK - Object Layer Attributes #1, Směr otevírání dveří: -; Object Layer Attributes #2, Status: Nový; Object Layer Attributes #2, Práce: Betonářské práce; Object Layer Attributes #2, Allright_Stavebni_dil_ID: 1852Dve0798434622; Object Layer Attributes #2, Jednotka: m3; Object Layer Attributes #2, Název_objektu: Dveřní otvor; Object Layer Attributes #2, Směr otevírání dveří: -
Prostup stěnou | Půdorys 5.NP | Betonářské práce | 1852SVý0798435893 | m3 | Stěnový výklenek | NEW | 0.023 | 0.2 | 0.005 | 0.15 | 0.15
Prostup stěnou | Půdorys 5.NP | Betonářské práce | 1852SVý0798435887 | m3 | Stěnový výklenek | NEW | 0.023 | 0.2 | 0.005 | 0.15 | 0.15
Prostup stěnou | Půdorys 5.NP | Betonářské práce | 1852SVý0798435881 | m3 | Stěnový výklenek | NEW | 0.023 | 0.2 | 0.005 | 0.15 | 0.15
Prostup stěnou | Půdorys 5.NP | Betonářské práce | 1852SVý0798435875 | m3 | Stěnový výklenek | NEW | 0.023 | 0.2 | 0.005 | 0.15 | 0.15
Prostup stěnou | Půdorys 5.NP | Betonářské práce | 1852SVý0798435869 | m3 | Stěnový výklenek | NEW | 0.023 | 0.2 | 0.005 | 0.15 | 0.15
Prostup stěnou | Půdorys 5.NP | Betonářské práce | 1852SVý0798435863 | m3 | Stěnový výklenek | NEW | 0.023 | 0.2 | 0.005 | 0.15 | 0.15
Prostup stěnou | Půdorys 5.NP | Betonářské práce | 1852SVý0798435857 | m3 | Stěnový výklenek | NEW | 0.023 | 0.2 | 0.005 | 0.15 | 0.15
Prostup stěnou | Půdorys 5.NP | Betonářské práce | 1852SVý0798435851 | m3 | Stěnový výklenek | NEW | 0.023 | 0.2 | 0.005 | 0.15 | 0.15
Prostup stěnou | Půdorys 5.NP | Betonářské práce | 1852SVý0798435845 | m3 | Stěnový výklenek | NEW | 0.023 | 0.2 | 0.005 | 0.15 | 0.15
Prostup stěnou | Půdorys 5.NP | Betonářské práce | 1852SVý0798435839 | m3 | Stěnový výklenek | NEW | 0.023 | 0.2 | 0.005 | 0.15 | 0.15
Prostup stěnou | Půdorys 5.NP | Betonářské práce | 1852SVý0798435833 | m3 | Stěnový výklenek | NEW | 0.023 | 0.2 | 0.005 | 0.15 | 0.15
Prostup stěnou | Půdorys 5.NP | Betonářské práce | 1852SVý0798435827 | m3 | Stěnový výklenek | NEW | 0.023 | 0.2 | 0.005 | 0.15 | 0.15
Prostup stěnou | Půdorys 5.NP | Betonářské práce | 1852SVý0798435821 | m3 | Stěnový výklenek | NEW | 0.023 | 0.2 | 0.005 | 0.15 | 0.15
Prostup stěnou | Půdorys 5.NP | Betonářské práce | 1852SVý0798435815 | m3 | Stěnový výklenek | NEW | 0.023 | 0.2 | 0.005 | 0.15 | 0.15
Prostup stěnou | Půdorys 5.NP | Betonářské práce | 1852SVý0798435809 | m3 | Stěnový výklenek | NEW | 0.023 | 0.2 | 0.005 | 0.15 | 0.15
Prostup stěnou | Půdorys 5.NP | Betonářské práce | 1852SVý0798435803 | m3 | Stěnový výklenek | NEW | 0.023 | 0.2 | 0.005 | 0.15 | 0.15
Prostup stěnou | Půdorys 5.NP | Betonářské práce | 1852SVý0798435797 | m3 | Stěnový výklenek | NEW | 0.023 | 0.2 | 0.005 | 0.15 | 0.15
Prostup stěnou | Půdorys 5.NP | Betonářské práce | 1852SVý0798435791 | m3 | Stěnový výklenek | NEW | 0.023 | 0.2 | 0.005 | 0.15 | 0.15
Prostup stěnou | Půdorys 5.NP | Betonářské práce | 1852SVý0798435784 | m3 | Stěnový výklenek | NEW | 0.023 | 0.2 | 0.005 | 0.15 | 0.15
Prostup stěnou | Půdorys 5.NP | Zednické práce | 1852SVý0798435611 | m3 | Stěnový výklenek | NEW | 0.023 | 0.32 | 0.007 | 0.15 | 0.15
Prostup stěnou | Půdorys 5.NP | Zednické práce | 1852SVý0798435617 | m3 | Stěnový výklenek | NEW | 0.023 | 0.32 | 0.007 | 0.15 | 0.15
Prostup stěnou | Půdorys 5.NP | Zednické práce | 1852SVý0798435935 | m3 | Stěnový výklenek | NEW | 0.023 | 0.2 | 0.005 | 0.15 | 0.15
Prostup stěnou | Půdorys 5.NP | Zednické práce | 1852SVý0798435929 | m3 | Stěnový výklenek | NEW | 0.023 | 0.2 | 0.005 | 0.15 | 0.15
Prostup stěnou | Půdorys 5.NP | Zednické práce | 1852SVý0798436009 | m3 | Stěnový výklenek | NEW | 0.023 | 0.25 | 0.006 | 0.15 | 0.15
Prostup stěnou | Půdorys 5.NP | Zednické práce | 1852SVý0798436015 | m3 | Stěnový výklenek | NEW | 0.023 | 0.25 | 0.006 | 0.15 | 0.15
Prostup stěnou | Půdorys 5.NP | Zednické práce | 1852SVý0798436003 | m3 | Stěnový výklenek | NEW | 0.023 | 0.25 | 0.006 | 0.15 | 0.15
Prostup stěnou | Půdorys 5.NP | Zednické práce | 1852SVý0798435997 | m3 | Stěnový výklenek | NEW | 0.023 | 0.25 | 0.006 | 0.15 | 0.15
Prostup stěnou | Půdorys 5.NP | Zednické práce | 1852SVý0798435991 | m3 | Stěnový výklenek | NEW | 0.023 | 0.25 | 0.006 | 0.15 | 0.15
Prostup stěnou | Půdorys 5.NP | Zednické práce | 1852SVý0798435977 | m3 | Stěnový výklenek | NEW | 0.023 | 0.25 | 0.006 | 0.15 | 0.15
Prostup stěnou | Půdorys 5.NP | Zednické práce | 1852SVý0798435985 | m3 | Stěnový výklenek | NEW | 0.023 | 0.25 | 0.006 | 0.15 | 0.15
Prostup stěnou | Půdorys 5.NP | Betonářské práce | 1852SVý0798435623 | m3 | Stěnový výklenek | NEW | 0.023 | 0.32 | 0.007 | 0.15 | 0.15
Prostup stěnou | Půdorys 5.NP | Betonářské práce | 1852SVý0798435629 | m3 | Stěnový výklenek | NEW | 0.023 | 0.32 | 0.007 | 0.15 | 0.15
Prostup stěnou | Půdorys 5.NP | Betonářské práce | 1852SVý0798435635 | m3 | Stěnový výklenek | NEW | 0.023 | 0.32 | 0.007 | 0.15 | 0.15
Prostup stěnou | Půdorys 5.NP | Betonářské práce | 1852SVý0798435641 | m3 | Stěnový výklenek | NEW | 0.023 | 0.32 | 0.007 | 0.15 | 0.15
Prostup stěnou | Půdorys 5.NP | Betonářské práce | 1852SVý0798435647 | m3 | Stěnový výklenek | NEW | 0.023 | 0.32 | 0.007 | 0.15 | 0.15
Prostup stěnou | Půdorys 5.NP | Betonářské práce | 1852SVý0798435653 | m3 | Stěnový výklenek | NEW | 0.023 | 0.32 | 0.007 | 0.15 | 0.15
Prostup stěnou | Půdorys 5.NP | Betonářské práce | 1852SVý0798435659 | m3 | Stěnový výklenek | NEW | 0.023 | 0.32 | 0.007 | 0.15 | 0.15
Prostup stěnou | Půdorys 5.NP | Betonářské práce | 1852SVý0798435665 | m3 | Stěnový výklenek | NEW | 0.023 | 0.32 | 0.007 | 0.15 | 0.15
Prostup stěnou | Půdorys 5.NP | Betonářské práce | 1852SVý0798435671 | m3 | Stěnový výklenek | NEW | 0.023 | 0.32 | 0.007 | 0.15 | 0.15
Prostup stěnou | Půdorys 5.NP | Betonářské práce | 1852SVý0798435677 | m3 | Stěnový výklenek | NEW | 0.023 | 0.32 | 0.007 | 0.15 | 0.15
Prostup stěnou | Půdorys 5.NP | Betonářské práce | 1852SVý0798435683 | m3 | Stěnový výklenek | NEW | 0.023 | 0.32 | 0.007 | 0.15 | 0.15
Prostup stěnou | Půdorys 5.NP | Betonářské práce | 1852SVý0798435689 | m3 | Stěnový výklenek | NEW | 0.023 | 0.32 | 0.007 | 0.15 | 0.15
Prostup stěnou | Půdorys 5.NP | Betonářské práce | 1852SVý0798435695 | m3 | Stěnový výklenek | NEW | 0.023 | 0.32 | 0.007 | 0.15 | 0.15
Prostup stěnou | Půdorys 5.NP | Betonářské práce | 1852SVý0798435701 | m3 | Stěnový výklenek | NEW | 0.023 | 0.32 | 0.007 | 0.15 | 0.15
Prostup stěnou | Půdorys 5.NP | Betonářské práce | 1852SVý0798435707 | m3 | Stěnový výklenek | NEW | 0.023 | 0.32 | 0.007 | 0.15 | 0.15
Prostup stěnou | Půdorys 5.NP | Betonářské práce | 1852SVý0798435713 | m3 | Stěnový výklenek | NEW | 0.023 | 0.32 | 0.007 | 0.15 | 0.15
Prostup stěnou | Půdorys 5.NP | Betonářské práce | 1852SVý0798435719 | m3 | Stěnový výklenek | NEW | 0.023 | 0.32 | 0.007 | 0.15 | 0.15
Prostup stěnou | Půdorys 5.NP | Betonářské práce | 1852SVý0798435725 | m3 | Stěnový výklenek | NEW | 0.023 | 0.32 | 0.007 | 0.15 | 0.15
Prostup stěnou | Půdorys 5.NP | Betonářské práce | 1852SVý0798435731 | m3 | Stěnový výklenek | NEW | 0.023 | 0.32 | 0.007 | 0.15 | 0.15
Prostup stěnou | Půdorys 5.NP | Betonářské práce | 1852SVý0798435737 | m3 | Stěnový výklenek | NEW | 0.023 | 0.32 | 0.007 | 0.15 | 0.15
Prostup stěnou | Půdorys 5.NP | Betonářské práce | 1852SVý0798435743 | m3 | Stěnový výklenek | NEW | 0.023 | 0.32 | 0.007 | 0.15 | 0.15
Prostup stěnou | Půdorys 5.NP | Betonářské práce | 1852SVý0798435749 | m3 | Stěnový výklenek | NEW | 0.023 | 0.32 | 0.007 | 0.15 | 0.15
Prostup stěnou | Půdorys 5.NP | Betonářské práce | 1852SVý0798435755 | m3 | Stěnový výklenek | NEW | 0.023 | 0.32 | 0.007 | 0.15 | 0.15
Prostup stěnou | Půdorys 5.NP | Betonářské práce | 1852SVý0798435761 | m3 | Stěnový výklenek | NEW | 0.023 | 0.32 | 0.007 | 0.15 | 0.15
Prostup stěnou | Půdorys 5.NP | Betonářské práce | 1852SVý0798435767 | m3 | Stěnový výklenek | NEW | 0.023 | 0.32 | 0.007 | 0.15 | 0.15
Prostup stěnou | Půdorys 5.NP | Betonářské práce | 1852SVý0798435773 | m3 | Stěnový výklenek | NEW | 0.023 | 0.32 | 0.007 | 0.15 | 0.15
Prostup stěnou | Půdorys 5.NP | Betonářské práce | 1852SVý0798435779 | m3 | Stěnový výklenek | NEW | 0.023 | 0.32 | 0.007 | 0.15 | 0.15
Prostup stěnou | Půdorys 5.NP | Betonářské práce | 1852SVý0798435899 | m3 | Stěnový výklenek | NEW | 0.023 | 0.2 | 0.005 | 0.15 | 0.15
Prostup stěnou | Půdorys 5.NP | Betonářské práce | 1852SVý0798435905 | m3 | Stěnový výklenek | NEW | 0.023 | 0.2 | 0.005 | 0.15 | 0.15
Prostup stěnou | Půdorys 5.NP | Betonářské práce | 1852SVý0798435911 | m3 | Stěnový výklenek | NEW | 0.023 | 0.2 | 0.005 | 0.15 | 0.15
Prostup stěnou | Půdorys 5.NP | Betonářské práce | 1852SVý0798435917 | m3 | Stěnový výklenek | NEW | 0.023 | 0.2 | 0.005 | 0.15 | 0.15
Prostup stěnou | Půdorys 5.NP | Betonářské práce | 1852SVý0798435923 | m3 | Stěnový výklenek | NEW | 0.023 | 0.2 | 0.005 | 0.15 | 0.15
Prostup stěnou | Půdorys 5.NP | Betonářské práce | 1852SVý0798435941 | m3 | Stěnový výklenek | NEW | 0.023 | 0.2 | 0.005 | 0.15 | 0.15
Prostup stěnou | Půdorys 5.NP | Betonářské práce | 1852SVý0798435947 | m3 | Stěnový výklenek | NEW | 0.023 | 0.2 | 0.005 | 0.15 | 0.15
Prostup stěnou | Půdorys 5.NP | Betonářské práce | 1852SVý0798435953 | m3 | Stěnový výklenek | NEW | 0.023 | 0.2 | 0.005 | 0.15 | 0.15
Prostup stěnou | Půdorys 5.NP | Betonářské práce | 1852SVý0798435959 | m3 | Stěnový výklenek | NEW | 0.023 | 0.2 | 0.005 | 0.15 | 0.15
Prostup stěnou | Půdorys 5.NP | Betonářské práce | 1852SVý0798435965 | m3 | Stěnový výklenek | NEW | 0.023 | 0.2 | 0.005 | 0.15 | 0.15
Prostup stěnou | Půdorys 5.NP | Betonářské práce | 1852SVý0798435519 | m3 | Stěnový výklenek | NEW | 0.023 | 0.32 | 0.007 | 0.15 | 0.15
Prostup stěnou | Půdorys 5.NP | Betonářské práce | 1852SVý0798435513 | m3 | Stěnový výklenek | NEW | 0.023 | 0.32 | 0.007 | 0.15 | 0.15
Prostup stěnou | Půdorys 5.NP | Betonářské práce | 1852SVý0798435507 | m3 | Stěnový výklenek | NEW | 0.023 | 0.32 | 0.007 | 0.15 | 0.15
Prostup stěnou | Půdorys 5.NP | Betonářské práce | 1852SVý0798435501 | m3 | Stěnový výklenek | NEW | 0.023 | 0.32 | 0.007 | 0.15 | 0.15
Prostup stěnou | Půdorys 5.NP | Betonářské práce | 1852SVý0798435495 | m3 | Stěnový výklenek | NEW | 0.023 | 0.32 | 0.007 | 0.15 | 0.15
Prostup stěnou | Půdorys 5.NP | Betonářské práce | 1852SVý0798435489 | m3 | Stěnový výklenek | NEW | 0.023 | 0.32 | 0.007 | 0.15 | 0.15
Prostup stěnou | Půdorys 5.NP | Betonářské práce | 1852SVý0798435482 | m3 | Stěnový výklenek | NEW | 0.023 | 0.32 | 0.007 | 0.15 | 0.15
Prostup stěnou | Půdorys 5.NP | Betonářské práce | 1852SVý0798435476 | m3 | Stěnový výklenek | NEW | 0.023 | 0.32 | 0.007 | 0.15 | 0.15
Prostup stěnou | Půdorys 5.NP | Betonářské práce | 1852SVý0798435456 | m3 | Stěnový výklenek | NEW | 0.023 | 0.32 | 0.007 | 0.15 | 0.15
Prostup stěnou | Půdorys 5.NP | Betonářské práce | 1852SVý0798435551 | m3 | Stěnový výklenek | NEW | 0.023 | 0.32 | 0.007 | 0.15 | 0.15
Prostup stěnou | Půdorys 5.NP | Betonářské práce | 1852SVý0798435557 | m3 | Stěnový výklenek | NEW | 0.023 | 0.32 | 0.007 | 0.15 | 0.15
Prostup stěnou | Půdorys 5.NP | Betonářské práce | 1852SVý0798435563 | m3 | Stěnový výklenek | NEW | 0.023 | 0.32 | 0.007 | 0.15 | 0.15
Prostup stěnou | Půdorys 5.NP | Betonářské práce | 1852SVý0798435545 | m3 | Stěnový výklenek | NEW | 0.023 | 0.32 | 0.007 | 0.15 | 0.15
Prostup stěnou | Půdorys 5.NP | Betonářské práce | 1852SVý0798435569 | m3 | Stěnový výklenek | NEW | 0.023 | 0.32 | 0.007 | 0.15 | 0.15
Prostup stěnou | Půdorys 5.NP | Betonářské práce | 1852SVý0798435575 | m3 | Stěnový výklenek | NEW | 0.023 | 0.32 | 0.007 | 0.15 | 0.15
Prostup stěnou | Půdorys 5.NP | Betonářské práce | 1852SVý0798435581 | m3 | Stěnový výklenek | NEW | 0.023 | 0.32 | 0.007 | 0.15 | 0.15
Prostup stěnou | Půdorys 5.NP | Betonářské práce | 1852SVý0798435587 | m3 | Stěnový výklenek | NEW | 0.023 | 0.32 | 0.007 | 0.15 | 0.15
Prostup stěnou | Půdorys 5.NP | Betonářské práce | 1852SVý0798435593 | m3 | Stěnový výklenek | NEW | 0.023 | 0.32 | 0.007 | 0.15 | 0.15
Prostup stěnou | Půdorys 5.NP | Betonářské práce | 1852SVý0798435599 | m3 | Stěnový výklenek | NEW | 0.023 | 0.32 | 0.007 | 0.15 | 0.15
Prostup stěnou | Půdorys 5.NP | Betonářské práce | 1852SVý0798435605 | m3 | Stěnový výklenek | NEW | 0.023 | 0.32 | 0.007 | 0.15 | 0.15
Prostup stěnou | Půdorys 5.NP | Zednické práce | 1852SVý0798435970 | m3 | Stěnový výklenek | NEW | 0.023 | 0.25 | 0.006 | 0.15 | 0.15
Prostup deskou | Půdorys 5.NP | Betonářské práce | 1854DOt0000000812 | m3 | Otvor v desce | NEW | 0.09 | 0.3 | 0.023 | 0.25 | 0.3
Prostup deskou | Půdorys 5.NP | Betonářské práce | 1854DOt0000002026 | m3 | Otvor v desce | NEW | 0.04 | 0.2 | 0.01 | 0.25 | 0.2
Prostup deskou | Půdorys 5.NP | Betonářské práce | 1854DOt0000001986 | m3 | Otvor v desce | NEW | 0.04 | 0.2 | 0.01 | 0.25 | 0.2
Prostup deskou | Půdorys 5.NP | Betonářské práce | 1854DOt0000002033 | m3 | Otvor v desce | NEW | 0.09 | 0.3 | 0.023 | 0.25 | 0.3
Prostup deskou | Půdorys 5.NP | Betonářské práce | 1854DOt0000002040 | m3 | Otvor v desce | NEW | 0.09 | 0.3 | 0.023 | 0.25 | 0.3
Prostup deskou | Půdorys 5.NP | Betonářské práce | 1854DOt0000002209 | m3 | Otvor v desce | NEW | 1.62 | 1.8 | 0.405 | 0.25 | 0.9
Prostup deskou | Půdorys 5.NP | Betonářské práce | 1854DOt0000002325 | m3 | Otvor v desce | NEW | 0.018 | 0.118 | 0 | -0.002 | 0.149
Prostup stěnou | Půdorys 6.NP | Zateplovací systémy | 1952SVý0000000185 | m2 | Stěnový výklenek | NEW | 0.3 | 0.4 | 0.03 | 0.5 | 0.6 | NEMSOK - Object Layer Attributes #2, Status: Nový; Object Layer Attributes #2, Práce: Zednické práce; Object Layer Attributes #2, Allright_Stavebni_dil_ID: 1952SVý0798427014; Object Layer Attributes #2, Jednotka: m3; Object Layer Attributes #2, Název_objektu: Stěnový výklenek
Dveřní otvor | Půdorys 6.NP | Betonářské práce | 1952Dve0798427135 | m3 | Dveřní otvor | NEW | 1.818 | 0.3 | 0.545 | 2.02 | 0.9 | NEMSOK - Object Layer Attributes #1, Směr otevírání dveří: P
Prostup stěnou | Půdorys 6.NP | Zateplovací systémy | 1952SVý0000001077 | m2 | Stěnový výklenek | NEW | 0.3 | 0.4 | 0.03 | 0.5 | 0.6 | NEMSOK - Object Layer Attributes #2, Status: Nový; Object Layer Attributes #2, Práce: Zednické práce; Object Layer Attributes #2, Allright_Stavebni_dil_ID: 1952SVý0798427393; Object Layer Attributes #2, Jednotka: m3; Object Layer Attributes #2, Název_objektu: Stěnový výklenek
Okenní otvor | Půdorys 6.NP | Zateplovací systémy | 1952Okn0000001075 | m2 | Okenní otvor | NEW | 4.08 | 0.4 | 0.408 | 1.85 | 2.4 | NEMSOK - Object Layer Attributes #2, Status: Nový; Object Layer Attributes #2, Práce: Zateplovací systémy; Object Layer Attributes #2, Allright_Stavebni_dil_ID: 1952Okn0798427401; Object Layer Attributes #2, Jednotka: m3; Object Layer Attributes #2, Název_objektu: Okenní otvor
Stěnová nika | Půdorys 6.NP | Zateplovací systémy | 1952SNi0000001076 | m2 | Stěnová nika | NEW | 1.08 | 0.1 | 0.108 | 0.45 | 2.4
Prostup stěnou | Půdorys 6.NP | Zateplovací systémy | 1952SVý0798429156 | m2 | Stěnový výklenek | NEW | 0.023 | 0.37 | 0.001 | 0.15 | 0.15 | NEMSOK - Object Layer Attributes #2, Status: Nový; Object Layer Attributes #2, Práce: Betonářské práce; Object Layer Attributes #2, Allright_Stavebni_dil_ID: 1952SVý0798429157; Object Layer Attributes #2, Jednotka: m3; Object Layer Attributes #2, Název_objektu: Stěnový výklenek
Prostup stěnou | Půdorys 6.NP | Zateplovací systémy | 1952SVý0798429223 | m2 | Stěnový výklenek | NEW | 0.023 | 0.37 | 0.001 | 0.15 | 0.15 | NEMSOK - Object Layer Attributes #2, Status: Nový; Object Layer Attributes #2, Práce: Betonářské práce; Object Layer Attributes #2, Allright_Stavebni_dil_ID: 1952SVý0798429222; Object Layer Attributes #2, Jednotka: m3; Object Layer Attributes #2, Název_objektu: Stěnový výklenek
Prostup stěnou | Půdorys 6.NP | Zateplovací systémy | 1952SVý0798429237 | m2 | Stěnový výklenek | NEW | 0.023 | 0.37 | 0.001 | 0.15 | 0.15 | NEMSOK - Object Layer Attributes #2, Status: Nový; Object Layer Attributes #2, Práce: Betonářské práce; Object Layer Attributes #2, Allright_Stavebni_dil_ID: 1952SVý0798429238; Object Layer Attributes #2, Jednotka: m3; Object Layer Attributes #2, Název_objektu: Stěnový výklenek
Prostup stěnou | Půdorys 6.NP | Zateplovací systémy | 1952SVý0798429251 | m2 | Stěnový výklenek | NEW | 0.023 | 0.37 | 0.001 | 0.15 | 0.15 | NEMSOK - Object Layer Attributes #2, Status: Nový; Object Layer Attributes #2, Práce: Betonářské práce; Object Layer Attributes #2, Allright_Stavebni_dil_ID: 1952SVý0798429250; Object Layer Attributes #2, Jednotka: m3; Object Layer Attributes #2, Název_objektu: Stěnový výklenek
Prostup stěnou | Půdorys 6.NP | Zateplovací systémy | 1952SVý0798429263 | m2 | Stěnový výklenek | NEW | 0.023 | 0.37 | 0.001 | 0.15 | 0.15 | NEMSOK - Object Layer Attributes #2, Status: Nový; Object Layer Attributes #2, Práce: Betonářské práce; Object Layer Attributes #2, Allright_Stavebni_dil_ID: 1952SVý0798429264; Object Layer Attributes #2, Jednotka: m3; Object Layer Attributes #2, Název_objektu: Stěnový výklenek
Prostup stěnou | Půdorys 6.NP | Zateplovací systémy | 1952SVý0798429277 | m2 | Stěnový výklenek | NEW | 0.023 | 0.37 | 0.001 | 0.15 | 0.15 | NEMSOK - Object Layer Attributes #2, Status: Nový; Object Layer Attributes #2, Práce: Betonářské práce; Object Layer Attributes #2, Allright_Stavebni_dil_ID: 1952SVý0798429276; Object Layer Attributes #2, Jednotka: m3; Object Layer Attributes #2, Název_objektu: Stěnový výklenek
Prostup stěnou | Půdorys 6.NP | Zateplovací systémy | 1952SVý0798429289 | m2 | Stěnový výklenek | NEW | 0.023 | 0.37 | 0.001 | 0.15 | 0.15 | NEMSOK - Object Layer Attributes #2, Status: Nový; Object Layer Attributes #2, Práce: Betonářské práce; Object Layer Attributes #2, Allright_Stavebni_dil_ID: 1952SVý0798429290; Object Layer Attributes #2, Jednotka: m3; Object Layer Attributes #2, Název_objektu: Stěnový výklenek
Prostup stěnou | Půdorys 6.NP | Zateplovací systémy | 1952SVý0798429303 | m2 | Stěnový výklenek | NEW | 0.023 | 0.37 | 0.001 | 0.15 | 0.15 | NEMSOK - Object Layer Attributes #2, Status: Nový; Object Layer Attributes #2, Práce: Betonářské práce; Object Layer Attributes #2, Allright_Stavebni_dil_ID: 1952SVý0798429302; Object Layer Attributes #2, Jednotka: m3; Object Layer Attributes #2, Název_objektu: Stěnový výklenek
Prostup stěnou | Půdorys 6.NP | Zateplovací systémy | 1952SVý0798429315 | m2 | Stěnový výklenek | NEW | 0.023 | 0.37 | 0.001 | 0.15 | 0.15 | NEMSOK - Object Layer Attributes #2, Status: Nový; Object Layer Attributes #2, Práce: Betonářské práce; Object Layer Attributes #2, Allright_Stavebni_dil_ID: 1952SVý0798429316; Object Layer Attributes #2, Jednotka: m3; Object Layer Attributes #2, Název_objektu: Stěnový výklenek
Prostup stěnou | Půdorys 6.NP | Zateplovací systémy | 1952SVý0798429329 | m2 | Stěnový výklenek | NEW | 0.023 | 0.37 | 0.001 | 0.15 | 0.15 | NEMSOK - Object Layer Attributes #2, Status: Nový; Object Layer Attributes #2, Práce: Betonářské práce; Object Layer Attributes #2, Allright_Stavebni_dil_ID: 1952SVý0798429328; Object Layer Attributes #2, Jednotka: m3; Object Layer Attributes #2, Název_objektu: Stěnový výklenek
Prostup stěnou | Půdorys 6.NP | Zateplovací systémy | 1952SVý0798429341 | m2 | Stěnový výklenek | NEW | 0.023 | 0.37 | 0.001 | 0.15 | 0.15 | NEMSOK - Object Layer Attributes #2, Status: Nový; Object Layer Attributes #2, Práce: Betonářské práce; Object Layer Attributes #2, Allright_Stavebni_dil_ID: 1952SVý0798429342; Object Layer Attributes #2, Jednotka: m3; Object Layer Attributes #2, Název_objektu: Stěnový výklenek
Prostup stěnou | Půdorys 6.NP | Zateplovací systémy | 1952SVý0798429355 | m2 | Stěnový výklenek | NEW | 0.023 | 0.37 | 0.001 | 0.15 | 0.15 | NEMSOK - Object Layer Attributes #2, Status: Nový; Object Layer Attributes #2, Práce: Betonářské práce; Object Layer Attributes #2, Allright_Stavebni_dil_ID: 1952SVý0798429354; Object Layer Attributes #2, Jednotka: m3; Object Layer Attributes #2, Název_objektu: Stěnový výklenek
Prostup stěnou | Půdorys 6.NP | Zateplovací systémy | 1952SVý0798429367 | m2 | Stěnový výklenek | NEW | 0.023 | 0.37 | 0.001 | 0.15 | 0.15 | NEMSOK - Object Layer Attributes #2, Status: Nový; Object Layer Attributes #2, Práce: Betonářské práce; Object Layer Attributes #2, Allright_Stavebni_dil_ID: 1952SVý0798429368; Object Layer Attributes #2, Jednotka: m3; Object Layer Attributes #2, Název_objektu: Stěnový výklenek
Prostup stěnou | Půdorys 6.NP | Zateplovací systémy | 1952SVý0798429388 | m2 | Stěnový výklenek | NEW | 0.023 | 0.37 | 0.001 | 0.15 | 0.15 | NEMSOK - Object Layer Attributes #2, Status: Nový; Object Layer Attributes #2, Práce: Betonářské práce; Object Layer Attributes #2, Allright_Stavebni_dil_ID: 1952SVý0798429389; Object Layer Attributes #2, Jednotka: m3; Object Layer Attributes #2, Název_objektu: Stěnový výklenek
Prostup stěnou | Půdorys 6.NP | Zateplovací systémy | 1952SVý0798429414 | m2 | Stěnový výklenek | NEW | 0.023 | 0.37 | 0.001 | 0.15 | 0.15 | NEMSOK - Object Layer Attributes #2, Status: Nový; Object Layer Attributes #2, Práce: Betonářské práce; Object Layer Attributes #2, Allright_Stavebni_dil_ID: 1952SVý0798429415; Object Layer Attributes #2, Jednotka: m3; Object Layer Attributes #2, Název_objektu: Stěnový výklenek
Prostup stěnou | Půdorys 6.NP | Zateplovací systémy | 1952SVý0798429428 | m2 | Stěnový výklenek | NEW | 0.023 | 0.37 | 0.001 | 0.15 | 0.15 | NEMSOK - Object Layer Attributes #2, Status: Nový; Object Layer Attributes #2, Práce: Betonářské práce; Object Layer Attributes #2, Allright_Stavebni_dil_ID: 1952SVý0798429427; Object Layer Attributes #2, Jednotka: m3; Object Layer Attributes #2, Název_objektu: Stěnový výklenek
Prostup stěnou | Půdorys 6.NP | Zateplovací systémy | 1952SVý0798429440 | m2 | Stěnový výklenek | NEW | 0.022 | 0.37 | 0.001 | 0.15 | 0.15 | NEMSOK - Object Layer Attributes #2, Status: Nový; Object Layer Attributes #2, Práce: Betonářské práce; Object Layer Attributes #2, Allright_Stavebni_dil_ID: 1952SVý0798429441; Object Layer Attributes #2, Jednotka: m3; Object Layer Attributes #2, Název_objektu: Stěnový výklenek
Prostup stěnou | Půdorys 6.NP | Zateplovací systémy | 1952SVý0798429402 | m2 | Stěnový výklenek | NEW | 0.023 | 0.37 | 0.001 | 0.15 | 0.15 | NEMSOK - Object Layer Attributes #2, Status: Nový; Object Layer Attributes #2, Práce: Betonářské práce; Object Layer Attributes #2, Allright_Stavebni_dil_ID: 1952SVý0798429401; Object Layer Attributes #2, Jednotka: m3; Object Layer Attributes #2, Název_objektu: Stěnový výklenek
Prostup stěnou | Půdorys 6.NP | Zateplovací systémy | 1952SVý0798429454 | m2 | Stěnový výklenek | NEW | 0.022 | 0.37 | 0.001 | 0.15 | 0.15 | NEMSOK - Object Layer Attributes #2, Status: Nový; Object Layer Attributes #2, Práce: Betonářské práce; Object Layer Attributes #2, Allright_Stavebni_dil_ID: 1952SVý0798429453; Object Layer Attributes #2, Jednotka: m3; Object Layer Attributes #2, Název_objektu: Stěnový výklenek
Prostup stěnou | Půdorys 6.NP | Zateplovací systémy | 1952SVý0798429466 | m2 | Stěnový výklenek | NEW | 0.023 | 0.37 | 0.001 | 0.15 | 0.15 | NEMSOK - Object Layer Attributes #2, Status: Nový; Object Layer Attributes #2, Práce: Betonářské práce; Object Layer Attributes #2, Allright_Stavebni_dil_ID: 1952SVý0798429467; Object Layer Attributes #2, Jednotka: m3; Object Layer Attributes #2, Název_objektu: Stěnový výklenek
Prostup stěnou | Půdorys 6.NP | Zateplovací systémy | 1952SVý0798429480 | m2 | Stěnový výklenek | NEW | 0.023 | 0.37 | 0.001 | 0.15 | 0.15 | NEMSOK - Object Layer Attributes #2, Status: Nový; Object Layer Attributes #2, Práce: Betonářské práce; Object Layer Attributes #2, Allright_Stavebni_dil_ID: 1952SVý0798429479; Object Layer Attributes #2, Jednotka: m3; Object Layer Attributes #2, Název_objektu: Stěnový výklenek
Prostup stěnou | Půdorys 6.NP | Zateplovací systémy | 1952SVý0798429732 | m2 | Stěnový výklenek | NEW | 0.023 | 0.35 | 0.001 | 0.15 | 0.15 | NEMSOK - Object Layer Attributes #2, Status: Nový; Object Layer Attributes #2, Práce: Zednické práce; Object Layer Attributes #2, Allright_Stavebni_dil_ID: 1952SVý0798429733; Object Layer Attributes #2, Jednotka: m3; Object Layer Attributes #2, Název_objektu: Stěnový výklenek
Prostup stěnou | Půdorys 6.NP | Zateplovací systémy | 1952SVý0798429763 | m2 | Stěnový výklenek | NEW | 0.023 | 0.35 | 0.001 | 0.15 | 0.15 | NEMSOK - Object Layer Attributes #2, Status: Nový; Object Layer Attributes #2, Práce: Zednické práce; Object Layer Attributes #2, Allright_Stavebni_dil_ID: 1952SVý0798429762; Object Layer Attributes #2, Jednotka: m3; Object Layer Attributes #2, Název_objektu: Stěnový výklenek
Prostup stěnou | Půdorys 6.NP | Zateplovací systémy | 1952SVý0798429775 | m2 | Stěnový výklenek | NEW | 0.023 | 0.35 | 0.001 | 0.15 | 0.15 | NEMSOK - Object Layer Attributes #2, Status: Nový; Object Layer Attributes #2, Práce: Zednické práce; Object Layer Attributes #2, Allright_Stavebni_dil_ID: 1952SVý0798429776; Object Layer Attributes #2, Jednotka: m3; Object Layer Attributes #2, Název_objektu: Stěnový výklenek
Prostup stěnou | Půdorys 6.NP | Zateplovací systémy | 1952SVý0798429789 | m2 | Stěnový výklenek | NEW | 0.023 | 0.35 | 0.001 | 0.15 | 0.15 | NEMSOK - Object Layer Attributes #2, Status: Nový; Object Layer Attributes #2, Práce: Zednické práce; Object Layer Attributes #2, Allright_Stavebni_dil_ID: 1952SVý0798429788; Object Layer Attributes #2, Jednotka: m3; Object Layer Attributes #2, Název_objektu: Stěnový výklenek
Prostup stěnou | Půdorys 6.NP | Zateplovací systémy | 1952SVý0798430020 | m2 | Stěnový výklenek | NEW | 0.023 | 0.45 | 0.007 | 0.15 | 0.15 | NEMSOK - Object Layer Attributes #2, Status: Nový; Object Layer Attributes #2, Práce: Zednické práce; Object Layer Attributes #2, Allright_Stavebni_dil_ID: 1952SVý0798430021; Object Layer Attributes #2, Jednotka: m3; Object Layer Attributes #2, Název_objektu: Stěnový výklenek
Prostup stěnou | Půdorys 6.NP | Zateplovací systémy | 1952SVý0798430034 | m2 | Stěnový výklenek | NEW | 0.023 | 0.45 | 0.007 | 0.15 | 0.15 | NEMSOK - Object Layer Attributes #2, Status: Nový; Object Layer Attributes #2, Práce: Zednické práce; Object Layer Attributes #2, Allright_Stavebni_dil_ID: 1952SVý0798430033; Object Layer Attributes #2, Jednotka: m3; Object Layer Attributes #2, Název_objektu: Stěnový výklenek
Prostup stěnou | Půdorys 6.NP | Zateplovací systémy | 1952SVý0798430046 | m2 | Stěnový výklenek | NEW | 0.023 | 0.45 | 0.007 | 0.15 | 0.15 | NEMSOK - Object Layer Attributes #2, Status: Nový; Object Layer Attributes #2, Práce: Zednické práce; Object Layer Attributes #2, Allright_Stavebni_dil_ID: 1952SVý0798430047; Object Layer Attributes #2, Jednotka: m3; Object Layer Attributes #2, Název_objektu: Stěnový výklenek
Prostup stěnou | Půdorys 6.NP | Zateplovací systémy | 1952SVý0798430060 | m2 | Stěnový výklenek | NEW | 0.023 | 0.45 | 0.007 | 0.15 | 0.15 | NEMSOK - Object Layer Attributes #2, Status: Nový; Object Layer Attributes #2, Práce: Zednické práce; Object Layer Attributes #2, Allright_Stavebni_dil_ID: 1952SVý0798430059; Object Layer Attributes #2, Jednotka: m3; Object Layer Attributes #2, Název_objektu: Stěnový výklenek
Prostup stěnou | Půdorys 6.NP | Zateplovací systémy | 1952SVý0798430072 | m2 | Stěnový výklenek | NEW | 0.023 | 0.45 | 0.007 | 0.15 | 0.15 | NEMSOK - Object Layer Attributes #2, Status: Nový; Object Layer Attributes #2, Práce: Zednické práce; Object Layer Attributes #2, Allright_Stavebni_dil_ID: 1952SVý0798430073; Object Layer Attributes #2, Jednotka: m3; Object Layer Attributes #2, Název_objektu: Stěnový výklenek
Prostup stěnou | Půdorys 6.NP | Zateplovací systémy | 1952SVý0798430086 | m2 | Stěnový výklenek | NEW | 0.023 | 0.45 | 0.007 | 0.15 | 0.15 | NEMSOK - Object Layer Attributes #2, Status: Nový; Object Layer Attributes #2, Práce: Zednické práce; Object Layer Attributes #2, Allright_Stavebni_dil_ID: 1952SVý0798430085; Object Layer Attributes #2, Jednotka: m3; Object Layer Attributes #2, Název_objektu: Stěnový výklenek
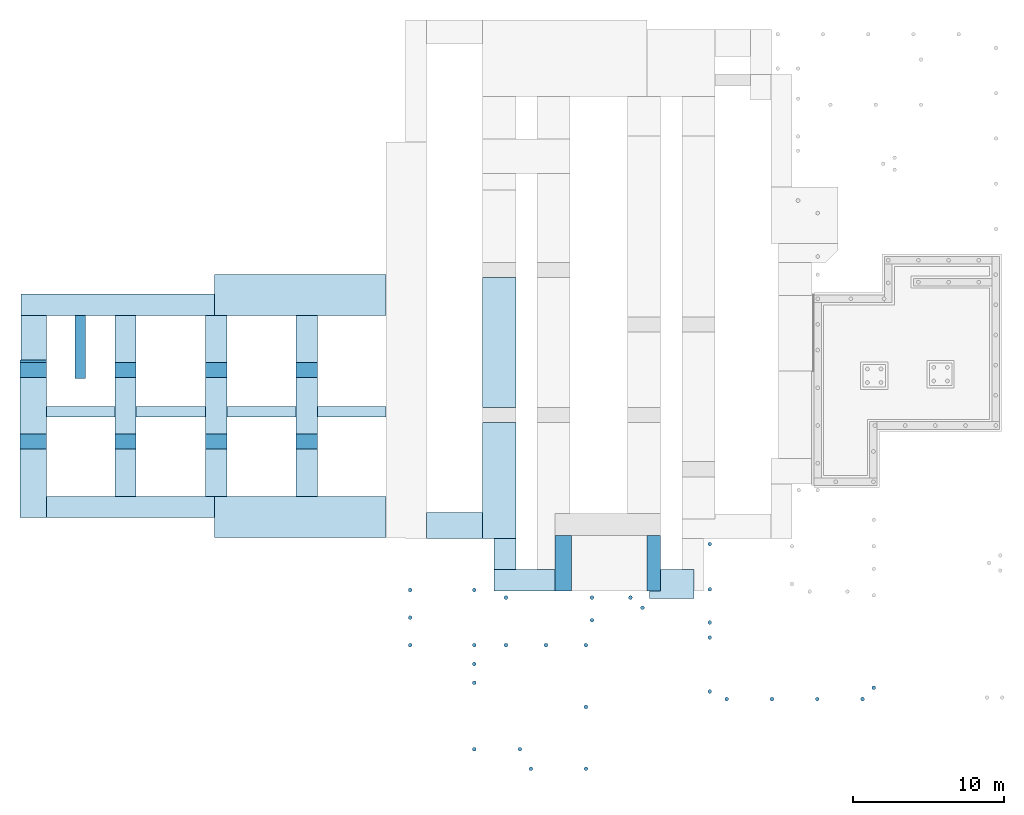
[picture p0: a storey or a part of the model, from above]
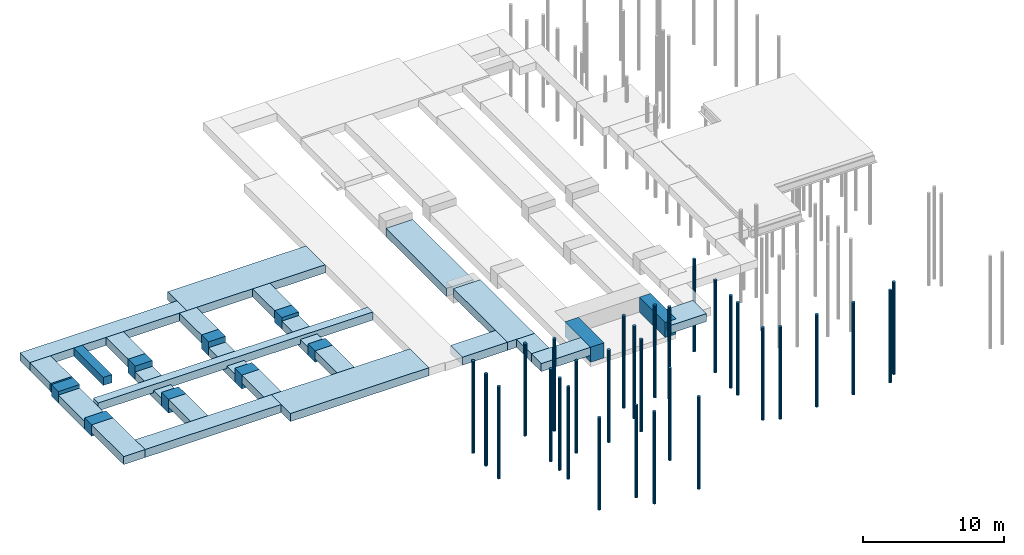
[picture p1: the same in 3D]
Properties of the parts of a building model (IFC4), part 20 of 45

# IfcOpeningElement: Opening (1638)
Name | In | Object Layer Attributes #1, Práce | Object Layer Attributes #1, Allright_Stavebni_dil_ID | Object Layer Attributes #1, Jednotka | Object Layer Attributes #1, Název_objektu | Status | Area (m2) | Depth (m) | Volume (m3) | Height (m) | Width (m)
Prostup stěnou | Půdorys 6.NP | Zateplovací systémy | 1952SVý0798430098 | m2 | Stěnový výklenek | NEW | 0.023 | 0.45 | 0.007 | 0.15 | 0.15 | NEMSOK - Object Layer Attributes #2, Status: Nový; Object Layer Attributes #2, Práce: Zednické práce; Object Layer Attributes #2, Allright_Stavebni_dil_ID: 1952SVý0798430099; Object Layer Attributes #2, Jednotka: m3; Object Layer Attributes #2, Název_objektu: Stěnový výklenek
Prostup stěnou | Půdorys 6.NP | Zateplovací systémy | 1952SVý0798430112 | m2 | Stěnový výklenek | NEW | 0.023 | 0.45 | 0.007 | 0.15 | 0.15 | NEMSOK - Object Layer Attributes #2, Status: Nový; Object Layer Attributes #2, Práce: Zednické práce; Object Layer Attributes #2, Allright_Stavebni_dil_ID: 1952SVý0798430111; Object Layer Attributes #2, Jednotka: m3; Object Layer Attributes #2, Název_objektu: Stěnový výklenek
Prostup stěnou | Půdorys 6.NP | Zateplovací systémy | 1952SVý0798429975 | m2 | Stěnový výklenek | NEW | 0.023 | 0.45 | 0.007 | 0.15 | 0.15 | NEMSOK - Object Layer Attributes #2, Status: Nový; Object Layer Attributes #2, Práce: Zednické práce; Object Layer Attributes #2, Allright_Stavebni_dil_ID: 1952SVý0798429974; Object Layer Attributes #2, Jednotka: m3; Object Layer Attributes #2, Název_objektu: Stěnový výklenek
Prostup stěnou | Půdorys 6.NP | Zateplovací systémy | 1952SVý0798429992 | m2 | Stěnový výklenek | NEW | 0.023 | 0.45 | 0.007 | 0.15 | 0.15 | NEMSOK - Object Layer Attributes #2, Status: Nový; Object Layer Attributes #2, Práce: Zednické práce; Object Layer Attributes #2, Allright_Stavebni_dil_ID: 1952SVý0798429993; Object Layer Attributes #2, Jednotka: m3; Object Layer Attributes #2, Název_objektu: Stěnový výklenek
Prostup stěnou | Půdorys 6.NP | Zateplovací systémy | 1952SVý0798430008 | m2 | Stěnový výklenek | NEW | 0.023 | 0.45 | 0.007 | 0.15 | 0.15 | NEMSOK - Object Layer Attributes #2, Status: Nový; Object Layer Attributes #2, Práce: Zednické práce; Object Layer Attributes #2, Allright_Stavebni_dil_ID: 1952SVý0798430007; Object Layer Attributes #2, Jednotka: m3; Object Layer Attributes #2, Název_objektu: Stěnový výklenek
Prostup stěnou | Půdorys 6.NP | Zateplovací systémy | 1952SVý0798429921 | m2 | Stěnový výklenek | NEW | 0.023 | 0.4 | 0.002 | 0.15 | 0.15 | NEMSOK - Object Layer Attributes #2, Status: Nový; Object Layer Attributes #2, Práce: Zednické práce; Object Layer Attributes #2, Allright_Stavebni_dil_ID: 1952SVý0798429922; Object Layer Attributes #2, Jednotka: m3; Object Layer Attributes #2, Název_objektu: Stěnový výklenek
Prostup stěnou | Půdorys 6.NP | Zateplovací systémy | 1952SVý0798429917 | m2 | Stěnový výklenek | NEW | 0.023 | 0.4 | 0.002 | 0.15 | 0.15 | NEMSOK - Object Layer Attributes #2, Status: Nový; Object Layer Attributes #2, Práce: Zednické práce; Object Layer Attributes #2, Allright_Stavebni_dil_ID: 1952SVý0798429916; Object Layer Attributes #2, Jednotka: m3; Object Layer Attributes #2, Název_objektu: Stěnový výklenek
Prostup stěnou | Půdorys 6.NP | Zateplovací systémy | 1952SVý0798429911 | m2 | Stěnový výklenek | NEW | 0.023 | 0.4 | 0.002 | 0.15 | 0.15 | NEMSOK - Object Layer Attributes #2, Status: Nový; Object Layer Attributes #2, Práce: Zednické práce; Object Layer Attributes #2, Allright_Stavebni_dil_ID: 1952SVý0798429912; Object Layer Attributes #2, Jednotka: m3; Object Layer Attributes #2, Název_objektu: Stěnový výklenek
Prostup stěnou | Půdorys 6.NP | Zateplovací systémy | 1952SVý0798429906 | m2 | Stěnový výklenek | NEW | 0.023 | 0.4 | 0.002 | 0.15 | 0.15 | NEMSOK - Object Layer Attributes #2, Status: Nový; Object Layer Attributes #2, Práce: Zednické práce; Object Layer Attributes #2, Allright_Stavebni_dil_ID: 1952SVý0798429905; Object Layer Attributes #2, Jednotka: m3; Object Layer Attributes #2, Název_objektu: Stěnový výklenek
Prostup stěnou | Půdorys 6.NP | Zateplovací systémy | 1952SVý0798429535 | m2 | Stěnový výklenek | NEW | 0.023 | 0.37 | 0.001 | 0.15 | 0.15 | NEMSOK - Object Layer Attributes #2, Status: Nový; Object Layer Attributes #2, Práce: Betonářské práce; Object Layer Attributes #2, Allright_Stavebni_dil_ID: 1952SVý0798429536; Object Layer Attributes #2, Jednotka: m3; Object Layer Attributes #2, Název_objektu: Stěnový výklenek
Prostup stěnou | Půdorys 6.NP | Zateplovací systémy | 1952SVý0798429532 | m2 | Stěnový výklenek | NEW | 0.023 | 0.37 | 0.001 | 0.15 | 0.15 | NEMSOK - Object Layer Attributes #2, Status: Nový; Object Layer Attributes #2, Práce: Betonářské práce; Object Layer Attributes #2, Allright_Stavebni_dil_ID: 1952SVý0798429531; Object Layer Attributes #2, Jednotka: m3; Object Layer Attributes #2, Název_objektu: Stěnový výklenek
Prostup stěnou | Půdorys 6.NP | Zateplovací systémy | 1952SVý0798429527 | m2 | Stěnový výklenek | NEW | 0.023 | 0.37 | 0.001 | 0.15 | 0.15 | NEMSOK - Object Layer Attributes #2, Status: Nový; Object Layer Attributes #2, Práce: Betonářské práce; Object Layer Attributes #2, Allright_Stavebni_dil_ID: 1952SVý0798429528; Object Layer Attributes #2, Jednotka: m3; Object Layer Attributes #2, Název_objektu: Stěnový výklenek
Prostup stěnou | Půdorys 6.NP | Zateplovací systémy | 1952SVý0798429524 | m2 | Stěnový výklenek | NEW | 0.023 | 0.37 | 0.001 | 0.15 | 0.15 | NEMSOK - Object Layer Attributes #2, Status: Nový; Object Layer Attributes #2, Práce: Betonářské práce; Object Layer Attributes #2, Allright_Stavebni_dil_ID: 1952SVý0798429523; Object Layer Attributes #2, Jednotka: m3; Object Layer Attributes #2, Název_objektu: Stěnový výklenek
Prostup stěnou | Půdorys 6.NP | Zateplovací systémy | 1952SVý0798429519 | m2 | Stěnový výklenek | NEW | 0.023 | 0.37 | 0.001 | 0.15 | 0.15 | NEMSOK - Object Layer Attributes #2, Status: Nový; Object Layer Attributes #2, Práce: Betonářské práce; Object Layer Attributes #2, Allright_Stavebni_dil_ID: 1952SVý0798429520; Object Layer Attributes #2, Jednotka: m3; Object Layer Attributes #2, Název_objektu: Stěnový výklenek
Prostup stěnou | Půdorys 6.NP | Zateplovací systémy | 1952SVý0798429516 | m2 | Stěnový výklenek | NEW | 0.023 | 0.37 | 0.001 | 0.15 | 0.15 | NEMSOK - Object Layer Attributes #2, Status: Nový; Object Layer Attributes #2, Práce: Betonářské práce; Object Layer Attributes #2, Allright_Stavebni_dil_ID: 1952SVý0798429515; Object Layer Attributes #2, Jednotka: m3; Object Layer Attributes #2, Název_objektu: Stěnový výklenek
Prostup stěnou | Půdorys 6.NP | Zateplovací systémy | 1952SVý0798429511 | m2 | Stěnový výklenek | NEW | 0.023 | 0.37 | 0.001 | 0.15 | 0.15 | NEMSOK - Object Layer Attributes #2, Status: Nový; Object Layer Attributes #2, Práce: Betonářské práce; Object Layer Attributes #2, Allright_Stavebni_dil_ID: 1952SVý0798429512; Object Layer Attributes #2, Jednotka: m3; Object Layer Attributes #2, Název_objektu: Stěnový výklenek
Prostup stěnou | Půdorys 6.NP | Zateplovací systémy | 1952SVý0798429508 | m2 | Stěnový výklenek | NEW | 0.023 | 0.37 | 0.001 | 0.15 | 0.15 | NEMSOK - Object Layer Attributes #2, Status: Nový; Object Layer Attributes #2, Práce: Betonářské práce; Object Layer Attributes #2, Allright_Stavebni_dil_ID: 1952SVý0798429507; Object Layer Attributes #2, Jednotka: m3; Object Layer Attributes #2, Název_objektu: Stěnový výklenek
Prostup stěnou | Půdorys 6.NP | Zateplovací systémy | 1952SVý0798429874 | m2 | Stěnový výklenek | NEW | 0.023 | 0.4 | 0.002 | 0.15 | 0.15 | NEMSOK - Object Layer Attributes #2, Status: Nový; Object Layer Attributes #2, Práce: Zednické práce; Object Layer Attributes #2, Allright_Stavebni_dil_ID: 1952SVý0798429873; Object Layer Attributes #2, Jednotka: m3; Object Layer Attributes #2, Název_objektu: Stěnový výklenek
Prostup stěnou | Půdorys 6.NP | Zateplovací systémy | 1952SVý0798429802 | m2 | Stěnový výklenek | NEW | 0.023 | 0.4 | 0.002 | 0.15 | 0.15 | NEMSOK - Object Layer Attributes #2, Status: Nový; Object Layer Attributes #2, Práce: Zednické práce; Object Layer Attributes #2, Allright_Stavebni_dil_ID: 1952SVý0798429801; Object Layer Attributes #2, Jednotka: m3; Object Layer Attributes #2, Název_objektu: Stěnový výklenek
Prostup stěnou | Půdorys 6.NP | Zateplovací systémy | 1952SVý0798429847 | m2 | Stěnový výklenek | NEW | 0.023 | 0.4 | 0.002 | 0.15 | 0.15 | NEMSOK - Object Layer Attributes #2, Status: Nový; Object Layer Attributes #2, Práce: Zednické práce; Object Layer Attributes #2, Allright_Stavebni_dil_ID: 1952SVý0798429846; Object Layer Attributes #2, Jednotka: m3; Object Layer Attributes #2, Název_objektu: Stěnový výklenek
Prostup stěnou | Půdorys 6.NP | Zateplovací systémy | 1952SVý0798429860 | m2 | Stěnový výklenek | NEW | 0.023 | 0.4 | 0.002 | 0.15 | 0.15 | NEMSOK - Object Layer Attributes #2, Status: Nový; Object Layer Attributes #2, Práce: Zednické práce; Object Layer Attributes #2, Allright_Stavebni_dil_ID: 1952SVý0798429861; Object Layer Attributes #2, Jednotka: m3; Object Layer Attributes #2, Název_objektu: Stěnový výklenek
Prostup stěnou | Půdorys 6.NP | Zateplovací systémy | 1952SVý0798429901 | m2 | Stěnový výklenek | NEW | 0.022 | 0.35 | 0.001 | 0.15 | 0.15 | NEMSOK - Object Layer Attributes #2, Status: Nový; Object Layer Attributes #2, Práce: Zednické práce; Object Layer Attributes #2, Allright_Stavebni_dil_ID: 1952SVý0798429902; Object Layer Attributes #2, Jednotka: m3; Object Layer Attributes #2, Název_objektu: Stěnový výklenek
Prostup stěnou | Půdorys 6.NP | Zateplovací systémy | 1952SVý0798429897 | m2 | Stěnový výklenek | NEW | 0.023 | 0.35 | 0.001 | 0.15 | 0.15 | NEMSOK - Object Layer Attributes #2, Status: Nový; Object Layer Attributes #2, Práce: Zednické práce; Object Layer Attributes #2, Allright_Stavebni_dil_ID: 1952SVý0798429896; Object Layer Attributes #2, Jednotka: m3; Object Layer Attributes #2, Název_objektu: Stěnový výklenek
Prostup stěnou | Půdorys 6.NP | Zateplovací systémy | 1952SVý0798429891 | m2 | Stěnový výklenek | NEW | 0.023 | 0.35 | 0.001 | 0.15 | 0.15 | NEMSOK - Object Layer Attributes #2, Status: Nový; Object Layer Attributes #2, Práce: Zednické práce; Object Layer Attributes #2, Allright_Stavebni_dil_ID: 1952SVý0798429892; Object Layer Attributes #2, Jednotka: m3; Object Layer Attributes #2, Název_objektu: Stěnový výklenek
Prostup stěnou | Půdorys 6.NP | Zateplovací systémy | 1952SVý0798429887 | m2 | Stěnový výklenek | NEW | 0.023 | 0.35 | 0.001 | 0.15 | 0.15 | NEMSOK - Object Layer Attributes #2, Status: Nový; Object Layer Attributes #2, Práce: Zednické práce; Object Layer Attributes #2, Allright_Stavebni_dil_ID: 1952SVý0798429886; Object Layer Attributes #2, Jednotka: m3; Object Layer Attributes #2, Název_objektu: Stěnový výklenek
Prostup deskou | Půdorys 6.NP | Betonářské práce | 1954DOt0000000710 | m3 | Otvor v desce | NEW | 0.54 | 0.6 | 0.038 | 0.07 | 0.9
Prostup deskou | Půdorys 6.NP | Izolace tepelné | 1966DOt0000000019 | m3 | Otvor v desce | NEW | 1.08 | 0.9 | 0.281 | 0.26 | 1.2
Prostup stěnou | Půdorys střechy | Zateplovací systémy | 2477SVý0000001009 | m2 | Stěnový výklenek | NEW | 0.023 | 0.35 | 0.002 | 0.15 | 0.15 | NEMSOK - Object Layer Attributes #2, Status: Nový; Object Layer Attributes #2, Práce: Zednické práce; Object Layer Attributes #2, Allright_Stavebni_dil_ID: 2477SVý0000001010; Object Layer Attributes #2, Jednotka: m3; Object Layer Attributes #2, Název_objektu: Stěnový výklenek
Prostup stěnou | Půdorys střechy | Zateplovací systémy | 2477SVý0000001021 | m2 | Stěnový výklenek | NEW | 0.023 | 0.35 | 0.002 | 0.15 | 0.15 | NEMSOK - Object Layer Attributes #2, Status: Nový; Object Layer Attributes #2, Práce: Zednické práce; Object Layer Attributes #2, Allright_Stavebni_dil_ID: 2477SVý0000001020; Object Layer Attributes #2, Jednotka: m3; Object Layer Attributes #2, Název_objektu: Stěnový výklenek
Prostup stěnou | Půdorys střechy | Zateplovací systémy | 2477SVý0000001031 | m2 | Stěnový výklenek | NEW | 0.023 | 0.35 | 0.002 | 0.15 | 0.15 | NEMSOK - Object Layer Attributes #2, Status: Nový; Object Layer Attributes #2, Práce: Zednické práce; Object Layer Attributes #2, Allright_Stavebni_dil_ID: 2477SVý0000001032; Object Layer Attributes #2, Jednotka: m3; Object Layer Attributes #2, Název_objektu: Stěnový výklenek
Prostup stěnou | Půdorys střechy | Zateplovací systémy | 2477SVý0000001043 | m2 | Stěnový výklenek | NEW | 0.023 | 0.35 | 0.002 | 0.15 | 0.15 | NEMSOK - Object Layer Attributes #2, Status: Nový; Object Layer Attributes #2, Práce: Zednické práce; Object Layer Attributes #2, Allright_Stavebni_dil_ID: 2477SVý0000001042; Object Layer Attributes #2, Jednotka: m3; Object Layer Attributes #2, Název_objektu: Stěnový výklenek
Prostup stěnou | Půdorys střechy | Zateplovací systémy | 2477SVý0000001053 | m2 | Stěnový výklenek | NEW | 0.023 | 0.35 | 0.002 | 0.15 | 0.15 | NEMSOK - Object Layer Attributes #2, Status: Nový; Object Layer Attributes #2, Práce: Zednické práce; Object Layer Attributes #2, Allright_Stavebni_dil_ID: 2477SVý0000001054; Object Layer Attributes #2, Jednotka: m3; Object Layer Attributes #2, Název_objektu: Stěnový výklenek
Prostup stěnou | Půdorys střechy | Zateplovací systémy | 2477SVý0000001065 | m2 | Stěnový výklenek | NEW | 0.023 | 0.35 | 0.002 | 0.15 | 0.15 | NEMSOK - Object Layer Attributes #2, Status: Nový; Object Layer Attributes #2, Práce: Zednické práce; Object Layer Attributes #2, Allright_Stavebni_dil_ID: 2477SVý0000001064; Object Layer Attributes #2, Jednotka: m3; Object Layer Attributes #2, Název_objektu: Stěnový výklenek
Prostup stěnou | Půdorys střechy | Zateplovací systémy | 2477SVý0000001075 | m2 | Stěnový výklenek | NEW | 0.023 | 0.35 | 0.002 | 0.15 | 0.15 | NEMSOK - Object Layer Attributes #2, Status: Nový; Object Layer Attributes #2, Práce: Zednické práce; Object Layer Attributes #2, Allright_Stavebni_dil_ID: 2477SVý0000001076; Object Layer Attributes #2, Jednotka: m3; Object Layer Attributes #2, Název_objektu: Stěnový výklenek
Prostup stěnou | Půdorys střechy | Zateplovací systémy | 2477SVý0000000973 | m2 | Stěnový výklenek | NEW | 0.023 | 0.35 | 0.002 | 0.15 | 0.15 | NEMSOK - Object Layer Attributes #2, Status: Nový; Object Layer Attributes #2, Práce: Zednické práce; Object Layer Attributes #2, Allright_Stavebni_dil_ID: 2477SVý0000000974; Object Layer Attributes #2, Jednotka: m3; Object Layer Attributes #2, Název_objektu: Stěnový výklenek
Prostup stěnou | Půdorys střechy | Zateplovací systémy | 2477SVý0000001108 | m2 | Stěnový výklenek | NEW | 0.023 | 0.35 | 0.002 | 0.15 | 0.15 | NEMSOK - Object Layer Attributes #2, Status: Nový; Object Layer Attributes #2, Práce: Zednické práce; Object Layer Attributes #2, Allright_Stavebni_dil_ID: 2477SVý0000001109; Object Layer Attributes #2, Jednotka: m3; Object Layer Attributes #2, Název_objektu: Stěnový výklenek
Prostup stěnou | Půdorys střechy | Zateplovací systémy | 2477SVý0000001098 | m2 | Stěnový výklenek | NEW | 0.023 | 0.35 | 0.002 | 0.15 | 0.15 | NEMSOK - Object Layer Attributes #2, Status: Nový; Object Layer Attributes #2, Práce: Zednické práce; Object Layer Attributes #2, Allright_Stavebni_dil_ID: 2477SVý0000001097; Object Layer Attributes #2, Jednotka: m3; Object Layer Attributes #2, Název_objektu: Stěnový výklenek
Prostup stěnou | Půdorys střechy | Zateplovací systémy | 2477SVý0000001085 | m2 | Stěnový výklenek | NEW | 0.023 | 0.35 | 0.002 | 0.15 | 0.15 | NEMSOK - Object Layer Attributes #2, Status: Nový; Object Layer Attributes #2, Práce: Zednické práce; Object Layer Attributes #2, Allright_Stavebni_dil_ID: 2477SVý0000001086; Object Layer Attributes #2, Jednotka: m3; Object Layer Attributes #2, Název_objektu: Stěnový výklenek
Prostup stěnou | Půdorys střechy | Zateplovací systémy | 2477SVý0000001196 | m2 | Stěnový výklenek | NEW | 0.023 | 0.35 | 0.002 | 0.15 | 0.15 | NEMSOK - Object Layer Attributes #2, Status: Nový; Object Layer Attributes #2, Práce: Zednické práce; Object Layer Attributes #2, Allright_Stavebni_dil_ID: 2477SVý0000001197; Object Layer Attributes #2, Jednotka: m3; Object Layer Attributes #2, Název_objektu: Stěnový výklenek
Prostup stěnou | Půdorys střechy | Zateplovací systémy | 2477SVý0000001186 | m2 | Stěnový výklenek | NEW | 0.023 | 0.35 | 0.002 | 0.15 | 0.15 | NEMSOK - Object Layer Attributes #2, Status: Nový; Object Layer Attributes #2, Práce: Zednické práce; Object Layer Attributes #2, Allright_Stavebni_dil_ID: 2477SVý0000001185; Object Layer Attributes #2, Jednotka: m3; Object Layer Attributes #2, Název_objektu: Stěnový výklenek
Prostup stěnou | Půdorys střechy | Zateplovací systémy | 2477SVý0000001174 | m2 | Stěnový výklenek | NEW | 0.023 | 0.35 | 0.002 | 0.15 | 0.15 | NEMSOK - Object Layer Attributes #2, Status: Nový; Object Layer Attributes #2, Práce: Zednické práce; Object Layer Attributes #2, Allright_Stavebni_dil_ID: 2477SVý0000001175; Object Layer Attributes #2, Jednotka: m3; Object Layer Attributes #2, Název_objektu: Stěnový výklenek
Prostup stěnou | Půdorys střechy | Zateplovací systémy | 2477SVý0000001164 | m2 | Stěnový výklenek | NEW | 0.023 | 0.35 | 0.002 | 0.15 | 0.15 | NEMSOK - Object Layer Attributes #2, Status: Nový; Object Layer Attributes #2, Práce: Zednické práce; Object Layer Attributes #2, Allright_Stavebni_dil_ID: 2477SVý0000001163; Object Layer Attributes #2, Jednotka: m3; Object Layer Attributes #2, Název_objektu: Stěnový výklenek
Prostup stěnou | Půdorys střechy | Zateplovací systémy | 2477SVý0000001152 | m2 | Stěnový výklenek | NEW | 0.023 | 0.35 | 0.002 | 0.15 | 0.15 | NEMSOK - Object Layer Attributes #2, Status: Nový; Object Layer Attributes #2, Práce: Zednické práce; Object Layer Attributes #2, Allright_Stavebni_dil_ID: 2477SVý0000001153; Object Layer Attributes #2, Jednotka: m3; Object Layer Attributes #2, Název_objektu: Stěnový výklenek
Prostup stěnou | Půdorys střechy | Zateplovací systémy | 2477SVý0000001142 | m2 | Stěnový výklenek | NEW | 0.023 | 0.35 | 0.002 | 0.15 | 0.15 | NEMSOK - Object Layer Attributes #2, Status: Nový; Object Layer Attributes #2, Práce: Zednické práce; Object Layer Attributes #2, Allright_Stavebni_dil_ID: 2477SVý0000001141; Object Layer Attributes #2, Jednotka: m3; Object Layer Attributes #2, Název_objektu: Stěnový výklenek
Prostup stěnou | Půdorys střechy | Zateplovací systémy | 2477SVý0000001130 | m2 | Stěnový výklenek | NEW | 0.023 | 0.35 | 0.002 | 0.15 | 0.15 | NEMSOK - Object Layer Attributes #2, Status: Nový; Object Layer Attributes #2, Práce: Zednické práce; Object Layer Attributes #2, Allright_Stavebni_dil_ID: 2477SVý0000001131; Object Layer Attributes #2, Jednotka: m3; Object Layer Attributes #2, Název_objektu: Stěnový výklenek
Prostup stěnou | Půdorys střechy | Zateplovací systémy | 2477SVý0000001120 | m2 | Stěnový výklenek | NEW | 0.023 | 0.35 | 0.002 | 0.15 | 0.15 | NEMSOK - Object Layer Attributes #2, Status: Nový; Object Layer Attributes #2, Práce: Zednické práce; Object Layer Attributes #2, Allright_Stavebni_dil_ID: 2477SVý0000001119; Object Layer Attributes #2, Jednotka: m3; Object Layer Attributes #2, Název_objektu: Stěnový výklenek
Prostup stěnou | Půdorys střechy | Zateplovací systémy | 2477SVý0000001240 | m2 | Stěnový výklenek | NEW | 0.023 | 0.35 | 0.002 | 0.15 | 0.15 | NEMSOK - Object Layer Attributes #2, Status: Nový; Object Layer Attributes #2, Práce: Zednické práce; Object Layer Attributes #2, Allright_Stavebni_dil_ID: 2477SVý0000001241; Object Layer Attributes #2, Jednotka: m3; Object Layer Attributes #2, Název_objektu: Stěnový výklenek
Prostup stěnou | Půdorys střechy | Zateplovací systémy | 2477SVý0000001230 | m2 | Stěnový výklenek | NEW | 0.023 | 0.35 | 0.002 | 0.15 | 0.15 | NEMSOK - Object Layer Attributes #2, Status: Nový; Object Layer Attributes #2, Práce: Zednické práce; Object Layer Attributes #2, Allright_Stavebni_dil_ID: 2477SVý0000001229; Object Layer Attributes #2, Jednotka: m3; Object Layer Attributes #2, Název_objektu: Stěnový výklenek
Prostup stěnou | Půdorys střechy | Zateplovací systémy | 2477SVý0000001218 | m2 | Stěnový výklenek | NEW | 0.023 | 0.35 | 0.002 | 0.15 | 0.15 | NEMSOK - Object Layer Attributes #2, Status: Nový; Object Layer Attributes #2, Práce: Zednické práce; Object Layer Attributes #2, Allright_Stavebni_dil_ID: 2477SVý0000001219; Object Layer Attributes #2, Jednotka: m3; Object Layer Attributes #2, Název_objektu: Stěnový výklenek
Prostup stěnou | Půdorys střechy | Zateplovací systémy | 2477SVý0000001208 | m2 | Stěnový výklenek | NEW | 0.023 | 0.35 | 0.002 | 0.15 | 0.15 | NEMSOK - Object Layer Attributes #2, Status: Nový; Object Layer Attributes #2, Práce: Zednické práce; Object Layer Attributes #2, Allright_Stavebni_dil_ID: 2477SVý0000001207; Object Layer Attributes #2, Jednotka: m3; Object Layer Attributes #2, Název_objektu: Stěnový výklenek

# IfcRailing (122)
PredefinedType: USERDEFINED
NEMSOK - V6: 0 m; V7: 0 m; V8: 0 m; V9: 0; Stavební prvek: Rail_Object; Plugin_Bezeichnung: Rail_Path; Plugin_Objektname: Rail_Macro; Výška (h): 0 m; Průměr (d): 0 m
Pset_RailingCommon - IsExternal: yes
Name | In | Práce | Délka (m) = Length (m) | Označení | Allright_Stavebni_dil_ID | Jednotka | Název_objektu | Status | Kód prvku | Podlaží
Rail_Path | Půdorys 1.PP | Klempířské práce | 17.45 | Rail_Path | 1352Záb0798479541 | Kus | Zábradlí | EXISTING | Material: TiZn; NEMSOK - Materiál: TiZn
NÁRAZOVÉ MADLO | Půdorys 1.PP | Suché stavební práce | 2.525 | NÁRAZOVÉ MADLO | 1364Záb0798527242 | m | I.OS1 | NEW | OV00.02.1012 | 1.PP
NÁRAZOVÉ MADLO | Půdorys 1.PP | Suché stavební práce | 1.675 | NÁRAZOVÉ MADLO | 1364Záb0798522048 | m | I.OS1 | NEW | OV00.02.1001 | 1.PP
NÁRAZOVÉ MADLO | Půdorys 1.PP | Suché stavební práce | 2.2 | NÁRAZOVÉ MADLO | 1364Záb0798522053 | m | I.OS1 | NEW | OV00.02.1002 | 1.PP
NÁRAZOVÉ MADLO | Půdorys 1.PP | Suché stavební práce | 0.3 | NÁRAZOVÉ MADLO | 1364Záb0798522058 | m | I.OS1 | NEW | OV00.02.1003 | 1.PP
NÁRAZOVÉ MADLO | Půdorys 1.PP | Suché stavební práce | 1.2 | NÁRAZOVÉ MADLO | 1364Záb0798522063 | m | I.OS1 | NEW | OV00.02.1004 | 1.PP
NÁRAZOVÉ MADLO | Půdorys 1.PP | Suché stavební práce | 6.3 | NÁRAZOVÉ MADLO | 1364Záb0798522068 | m | I.OS1 | NEW | OV00.02.1005 | 1.PP
NÁRAZOVÉ MADLO | Půdorys 1.PP | Suché stavební práce | 8.125 | NÁRAZOVÉ MADLO | 1364Záb0798522073 | m | I.OS1 | NEW | OV00.02.1006 | 1.PP
NÁRAZOVÉ MADLO | Půdorys 1.PP | Suché stavební práce | 0.4 | NÁRAZOVÉ MADLO | 1364Záb0798522078 | m | I.OS1 | NEW | OV00.02.1007 | 1.PP
NÁRAZOVÉ MADLO | Půdorys 1.PP | Suché stavební práce | 2.25 | NÁRAZOVÉ MADLO | 1364Záb0798522083 | m | I.OS1 | NEW | OV00.02.1008 | 1.PP
NÁRAZOVÉ MADLO | Půdorys 1.PP | Suché stavební práce | 6.8 | NÁRAZOVÉ MADLO | 1364Záb0798522088 | m | I.OS1 | NEW | OV00.02.1009 | 1.PP
NÁRAZOVÉ MADLO | Půdorys 1.PP | Suché stavební práce | 5.105 | NÁRAZOVÉ MADLO | 1364Záb0798529564 | m | I.OS1 | NEW | OV00.02.1014 | 1.PP
NÁRAZOVÉ MADLO | Půdorys 1.PP | Suché stavební práce | 1.3 | NÁRAZOVÉ MADLO | 1364Záb0798529535 | m | I.OS1 | NEW | OV00.02.1013 | 1.PP
NÁRAZOVÉ MADLO | Půdorys 1.PP | Suché stavební práce | 0.47 | NÁRAZOVÉ MADLO | 1364Záb0798522103 | m | I.OS1 | NEW | OV00.02.1010 | 1.PP
OCHRANA ROHŮ | Půdorys 1.PP | Suché stavební práce | 0.012 | OCHRANA ROHŮ | 1364Záb0798526238 | Kus | I.OS3 | NEW | OV00.02.3006 | 1.PP
OCHRANA ROHŮ | Půdorys 1.PP | Suché stavební práce | 0.012 | OCHRANA ROHŮ | 1364Záb0798526220 | Kus | I.OS3 | NEW | OV00.02.3004 | 1.PP
OCHRANA ROHŮ | Půdorys 1.PP | Suché stavební práce | 0.012 | OCHRANA ROHŮ | 1364Záb0798526229 | Kus | I.OS3 | NEW | OV00.02.3005 | 1.PP
OCHRANA ROHŮ | Půdorys 1.PP | Suché stavební práce | 0.012 | OCHRANA ROHŮ | 1364Záb0798526211 | Kus | I.OS3 | NEW | OV00.02.3003 | 1.PP
OCHRANA ROHŮ | Půdorys 1.PP | Suché stavební práce | 0.012 | OCHRANA ROHŮ | 1364Záb0798526202 | Kus | I.OS3 | NEW | OV00.02.3002 | 1.PP
OCHRANA ROHŮ | Půdorys 1.PP | Suché stavební práce | 0.012 | OCHRANA ROHŮ | 1364Záb0798561757 | Kus | I.OS3 | NEW | OV00.02.3010 | 1.PP
OCHRANA ROHŮ | Půdorys 1.PP | Suché stavební práce | 0.012 | OCHRANA ROHŮ | 1364Záb0798526157 | Kus | I.OS3 | NEW | OV00.02.3001 | 1.PP
OCHRANA ROHŮ | Půdorys 1.PP | Suché stavební práce | 0.012 | OCHRANA ROHŮ | 1364Záb0798526986 | Kus | I.OS3 | NEW | OV00.02.3007 | 1.PP
OCHRANA ROHŮ | Půdorys 1.PP | Suché stavební práce | 0.012 | OCHRANA ROHŮ | 1364Záb0798526989 | Kus | I.OS3 | NEW | OV00.02.3008 | 1.PP
OCHRANA ROHŮ | Půdorys 1.PP | Suché stavební práce | 0.012 | OCHRANA ROHŮ | 1364Záb0798526992 | Kus | I.OS3 | NEW | OV00.02.3009 | 1.PP
OCHRANA ROHŮ | Půdorys 1.PP | Suché stavební práce | 0.012 | OCHRANA ROHŮ | 1364Záb0798561792 | Kus | I.OS3 | NEW | OV00.02.3011 | 1.PP
NÁRAZOVÉ MADLO | Půdorys 1.PP | Suché stavební práce | 3.9 | NÁRAZOVÉ MADLO | 1364Záb0798524478 | m | I.OS1 | NEW | OV00.02.1011 | 1.PP
NÁRAZOVÉ MADLO | Půdorys 1.PP | Suché stavební práce | 2.6 | NÁRAZOVÉ MADLO | 1364Záb0798607010 | m | I.OS1 | NEW | OV00.02.1015 | 1.PP
NÁRAZOVÉ MADLO | Půdorys 1.PP | Suché stavební práce | 1.8 | NÁRAZOVÉ MADLO | 1364Záb0798607019 | m | I.OS1 | NEW | OV00.02.1016 | 1.PP
OCHRANA ROHŮ | Půdorys 1.NP | Zámečnické práce | 0.012 | OCHRANA ROHŮ | 1464Záb1096232770 | Kus | I.OS3 | NEW | OV00.03.3022 | 1.NP
OCHRANA ROHŮ | Půdorys 1.NP | Zámečnické práce | 0.012 | OCHRANA ROHŮ | 1464Záb1096232815 | Kus | I.OS3 | NEW | OV00.03.3024 | 1.NP
OCHRANA ROHŮ | Půdorys 1.NP | Zámečnické práce | 0.012 | OCHRANA ROHŮ | 1464Záb1096230186 | Kus | I.OS3 | NEW | OV00.03.3001 | 1.NP
OCHRANA ROHŮ | Půdorys 1.NP | Zámečnické práce | 0.012 | OCHRANA ROHŮ | 1464Záb1096230189 | Kus | I.OS3 | NEW | OV00.03.3002 | 1.NP
OCHRANA ROHŮ | Půdorys 1.NP | Zámečnické práce | 0.012 | OCHRANA ROHŮ | 1464Záb1096230192 | Kus | I.OS3 | NEW | OV00.03.3003 | 1.NP
OCHRANA ROHŮ | Půdorys 1.NP | Zámečnické práce | 0.012 | OCHRANA ROHŮ | 1464Záb1096230195 | Kus | I.OS3 | NEW | OV00.03.3004 | 1.NP
OCHRANA ROHŮ | Půdorys 1.NP | Zámečnické práce | 0.012 | OCHRANA ROHŮ | 1464Záb1096230198 | Kus | I.OS3 | NEW | OV00.03.3005 | 1.NP
OCHRANA ROHŮ | Půdorys 1.NP | Zámečnické práce | 0.012 | OCHRANA ROHŮ | 1464Záb1096230201 | Kus | I.OS3 | NEW | OV00.03.3044 | 1.NP
OCHRANA ROHŮ | Půdorys 1.NP | Zámečnické práce | 0.012 | OCHRANA ROHŮ | 1464Záb1096230204 | Kus | I.OS3 | NEW | OV00.03.3045 | 1.NP
OCHRANA ROHŮ | Půdorys 1.NP | Zámečnické práce | 0.012 | OCHRANA ROHŮ | 1464Záb1096230225 | Kus | I.OS3 | NEW | OV00.03.3006 | 1.NP
OCHRANA ROHŮ | Půdorys 1.NP | Zámečnické práce | 0.012 | OCHRANA ROHŮ | 1464Záb1096232779 | Kus | I.OS3 | NEW | OV00.03.3023 | 1.NP
OCHRANA ROHŮ | Půdorys 1.NP | Zámečnické práce | 0.012 | OCHRANA ROHŮ | 1464Záb1096230384 | Kus | I.OS3 | NEW | OV00.03.3007 | 1.NP
OCHRANA ROHŮ | Půdorys 1.NP | Zámečnické práce | 0.012 | OCHRANA ROHŮ | 1464Záb1096230387 | Kus | I.OS3 | NEW | OV00.03.3008 | 1.NP
OCHRANA ROHŮ | Půdorys 1.NP | Zámečnické práce | 0.012 | OCHRANA ROHŮ | 1464Záb1096230390 | Kus | I.OS3 | NEW | OV00.03.3009 | 1.NP
OCHRANA ROHŮ | Půdorys 1.NP | Zámečnické práce | 0.012 | OCHRANA ROHŮ | 1464Záb1096230393 | Kus | I.OS3 | NEW | OV00.03.3010 | 1.NP
OCHRANA ROHŮ | Půdorys 1.NP | Zámečnické práce | 0.012 | OCHRANA ROHŮ | 1464Záb1096230396 | Kus | I.OS3 | NEW | OV00.03.3011 | 1.NP
OCHRANA ROHŮ | Půdorys 1.NP | Zámečnické práce | 0.012 | OCHRANA ROHŮ | 1464Záb1096230399 | Kus | I.OS3 | NEW | OV00.03.3012 | 1.NP
OCHRANA ROHŮ | Půdorys 1.NP | Zámečnické práce | 0.012 | OCHRANA ROHŮ | 1464Záb1096230402 | Kus | I.OS3 | NEW | OV00.03.3013 | 1.NP
OCHRANA ROHŮ | Půdorys 1.NP | Zámečnické práce | 0.012 | OCHRANA ROHŮ | 1464Záb1096230405 | Kus | I.OS3 | NEW | OV00.03.3014 | 1.NP
OCHRANA ROHŮ | Půdorys 1.NP | Zámečnické práce | 0.012 | OCHRANA ROHŮ | 1464Záb1096230408 | Kus | I.OS3 | NEW | OV00.03.3015 | 1.NP
OCHRANA ROHŮ | Půdorys 1.NP | Zámečnické práce | 0.012 | OCHRANA ROHŮ | 1464Záb1096230411 | Kus | I.OS3 | NEW | OV00.03.3016 | 1.NP
OCHRANA ROHŮ | Půdorys 1.NP | Zámečnické práce | 0.012 | OCHRANA ROHŮ | 1464Záb1096230414 | Kus | I.OS3 | NEW | OV00.03.3017 | 1.NP
OCHRANA ROHŮ | Půdorys 1.NP | Zámečnické práce | 0.012 | OCHRANA ROHŮ | 1464Záb1096230417 | Kus | I.OS3 | NEW | OV00.03.3018 | 1.NP
OCHRANA ROHŮ | Půdorys 1.NP | Zámečnické práce | 0.012 | OCHRANA ROHŮ | 1464Záb1096230420 | Kus | I.OS3 | NEW | OV00.03.3019 | 1.NP
OCHRANA ROHŮ | Půdorys 1.NP | Zámečnické práce | 0.012 | OCHRANA ROHŮ | 1464Záb1096230438 | Kus | I.OS3 | NEW | OV00.03.3021 | 1.NP
OCHRANA ROHŮ | Půdorys 1.NP | Zámečnické práce | 0.012 | OCHRANA ROHŮ | 1464Záb1096230429 | Kus | I.OS3 | NEW | OV00.03.3020 | 1.NP
NÁRAZOVÉ SVODIDLO | Půdorys 1.NP | Zámečnické práce | 1.6 | NÁRAZOVÉ SVODIDLO | 1464Záb1096231250 | m | I.OS2 | NEW | OV00.03.2001 | 1.NP
NÁRAZOVÉ SVODIDLO | Půdorys 1.NP | Zámečnické práce | 4.575 | NÁRAZOVÉ SVODIDLO | 1464Záb1096277164 | m | I.OS2 | NEW | OV00.03.2007 | 1.NP
NÁRAZOVÉ SVODIDLO | Půdorys 1.NP | Zámečnické práce | 5.2 | NÁRAZOVÉ SVODIDLO | 1464Záb1096288407 | m | I.OS2 | NEW | OV00.03.2009 | 1.NP
NÁRAZOVÉ SVODIDLO | Půdorys 1.NP | Zámečnické práce | 4.175 | NÁRAZOVÉ SVODIDLO | 1464Záb1096289284 | m | I.OS2 | NEW | OV00.03.2011 | 1.NP
NÁRAZOVÉ SVODIDLO | Půdorys 1.NP | Zámečnické práce | 5.625 | NÁRAZOVÉ SVODIDLO | 1464Záb1096289293 | m | I.OS2 | NEW | OV00.03.2012 | 1.NP
NÁRAZOVÉ SVODIDLO | Půdorys 1.NP | Zámečnické práce | 2.805 | NÁRAZOVÉ SVODIDLO | 1464Záb1096231259 | m | I.OS2 | NEW | OV00.03.2002 | 1.NP
NÁRAZOVÉ SVODIDLO | Půdorys 1.NP | Zámečnické práce | 1.308 | NÁRAZOVÉ SVODIDLO | 1464Záb1096231268 | m | I.OS2 | NEW | OV00.03.2003 | 1.NP
NÁRAZOVÉ SVODIDLO | Půdorys 1.NP | Zámečnické práce | 1.674 | NÁRAZOVÉ SVODIDLO | 1464Záb1096231277 | m | I.OS2 | NEW | OV00.03.2004 | 1.NP
NÁRAZOVÉ SVODIDLO | Půdorys 1.NP | Zámečnické práce | 2.27 | NÁRAZOVÉ SVODIDLO | 1464Záb1096231286 | m | I.OS2 | NEW | OV00.03.2005 | 1.NP
NÁRAZOVÉ SVODIDLO | Půdorys 1.NP | Zámečnické práce | 1.2 | NÁRAZOVÉ SVODIDLO | 1464Záb1096231295 | m | I.OS2 | NEW | OV00.03.2006 | 1.NP
NÁRAZOVÉ SVODIDLO | Půdorys 1.NP | Zámečnické práce | 1.514 | NÁRAZOVÉ SVODIDLO | 1464Záb1096301085 | m | I.OS2 | NEW | OV00.03.2013 | 1.NP
OCHRANA ROHŮ | Půdorys 1.NP | Zámečnické práce | 0.012 | OCHRANA ROHŮ | 1464Záb1096232824 | Kus | I.OS3 | NEW | OV00.03.3025 | 1.NP
OCHRANA ROHŮ | Půdorys 1.NP | Zámečnické práce | 0.012 | OCHRANA ROHŮ | 1464Záb1096232827 | Kus | I.OS3 | NEW | OV00.03.3026 | 1.NP
OCHRANA ROHŮ | Půdorys 1.NP | Zámečnické práce | 0.012 | OCHRANA ROHŮ | 1464Záb1096232830 | Kus | I.OS3 | NEW | OV00.03.3027 | 1.NP
OCHRANA ROHŮ | Půdorys 1.NP | Zámečnické práce | 0.012 | OCHRANA ROHŮ | 1464Záb1096232833 | Kus | I.OS3 | NEW | OV00.03.3028 | 1.NP
OCHRANA ROHŮ | Půdorys 1.NP | Zámečnické práce | 0.012 | OCHRANA ROHŮ | 1464Záb1096232836 | Kus | I.OS3 | NEW | OV00.03.3029 | 1.NP
OCHRANA ROHŮ | Půdorys 1.NP | Zámečnické práce | 0.012 | OCHRANA ROHŮ | 1464Záb1096232839 | Kus | I.OS3 | NEW | OV00.03.3030 | 1.NP
OCHRANA ROHŮ | Půdorys 1.NP | Zámečnické práce | 0.012 | OCHRANA ROHŮ | 1464Záb1096232842 | Kus | I.OS3 | NEW | OV00.03.3031 | 1.NP
OCHRANA ROHŮ | Půdorys 1.NP | Zámečnické práce | 0.012 | OCHRANA ROHŮ | 1464Záb1096232845 | Kus | I.OS3 | NEW | OV00.03.3032 | 1.NP
OCHRANA ROHŮ | Půdorys 1.NP | Zámečnické práce | 0.012 | OCHRANA ROHŮ | 1464Záb1096232848 | Kus | I.OS3 | NEW | OV00.03.3033 | 1.NP
OCHRANA ROHŮ | Půdorys 1.NP | Zámečnické práce | 0.012 | OCHRANA ROHŮ | 1464Záb1096232851 | Kus | I.OS3 | NEW | OV00.03.3034 | 1.NP
OCHRANA ROHŮ | Půdorys 1.NP | Zámečnické práce | 0.012 | OCHRANA ROHŮ | 1464Záb1096232854 | Kus | I.OS3 | NEW | OV00.03.3035 | 1.NP
OCHRANA ROHŮ | Půdorys 1.NP | Zámečnické práce | 0.012 | OCHRANA ROHŮ | 1464Záb1096232857 | Kus | I.OS3 | NEW | OV00.03.3036 | 1.NP
OCHRANA ROHŮ | Půdorys 1.NP | Zámečnické práce | 0.012 | OCHRANA ROHŮ | 1464Záb1096232860 | Kus | I.OS3 | NEW | OV00.03.3037 | 1.NP
OCHRANA ROHŮ | Půdorys 1.NP | Zámečnické práce | 0.012 | OCHRANA ROHŮ | 1464Záb1096232863 | Kus | I.OS3 | NEW | OV00.03.3038 | 1.NP
OCHRANA ROHŮ | Půdorys 1.NP | Zámečnické práce | 0.012 | OCHRANA ROHŮ | 1464Záb1096232866 | Kus | I.OS3 | NEW | OV00.03.3039 | 1.NP
OCHRANA ROHŮ | Půdorys 1.NP | Zámečnické práce | 0.012 | OCHRANA ROHŮ | 1464Záb1096232880 | Kus | I.OS3 | NEW | OV00.03.3040 | 1.NP
OCHRANA ROHŮ | Půdorys 1.NP | Zámečnické práce | 0.012 | OCHRANA ROHŮ | 1464Záb1096232883 | Kus | I.OS3 | NEW | OV00.03.3041 | 1.NP
OCHRANA ROHŮ | Půdorys 1.NP | Zámečnické práce | 0.012 | OCHRANA ROHŮ | 1464Záb1096232886 | Kus | I.OS3 | NEW | OV00.03.3042 | 1.NP
OCHRANA ROHŮ | Půdorys 1.NP | Zámečnické práce | 0.012 | OCHRANA ROHŮ | 1464Záb1096232889 | Kus | I.OS3 | NEW | OV00.03.3043 | 1.NP
OCHRANA ROHŮ | Půdorys 1.NP | Zámečnické práce | 0.012 | OCHRANA ROHŮ | 1464Záb1096238576 | Kus | II.OS3 | NEW | OV02.03.3001 | 1.NP
OCHRANA ROHŮ | Půdorys 1.NP | Zámečnické práce | 0.012 | OCHRANA ROHŮ | 1464Záb1096238581 | Kus | II.OS3 | NEW | OV02.03.3002 | 1.NP
OCHRANA ROHŮ | Půdorys 1.NP | Zámečnické práce | 0.012 | OCHRANA ROHŮ | 1464Záb1096238584 | Kus | II.OS3 | NEW | OV02.03.3003 | 1.NP
OCHRANA ROHŮ | Půdorys 1.NP | Zámečnické práce | 0.012 | OCHRANA ROHŮ | 1464Záb1096238587 | Kus | II.OS3 | NEW | OV02.03.3004 | 1.NP
OCHRANA ROHŮ | Půdorys 1.NP | Zámečnické práce | 0.012 | OCHRANA ROHŮ | 1464Záb1096238590 | Kus | II.OS3 | NEW | OV02.03.3005 | 1.NP
OCHRANA ROHŮ | Půdorys 1.NP | Zámečnické práce | 0.012 | OCHRANA ROHŮ | 1464Záb1096238593 | Kus | II.OS3 | NEW | OV02.03.3006 | 1.NP
OCHRANA ROHŮ | Půdorys 1.NP | Zámečnické práce | 0.012 | OCHRANA ROHŮ | 1464Záb1096238596 | Kus | II.OS3 | NEW | OV02.03.3007 | 1.NP
NÁRAZOVÉ MADLO | Půdorys 1.NP | Zámečnické práce | 8.425 | NÁRAZOVÉ MADLO | 1464Záb1096238626 | m | II.OS1 | NEW | OV02.03.1001 | 1.NP
NÁRAZOVÉ MADLO | Půdorys 1.NP | Zámečnické práce | 4 | NÁRAZOVÉ MADLO | 1464Záb1096238635 | m | II.OS1 | NEW | OV02.03.1002 | 1.NP
NÁRAZOVÉ MADLO | Půdorys 1.NP | Zámečnické práce | 1.15 | NÁRAZOVÉ MADLO | 1464Záb1096238644 | m | II.OS1 | NEW | OV02.03.1003 | 1.NP
NÁRAZOVÉ SVODIDLO | Půdorys 1.NP | Zámečnické práce | 8.775 | NÁRAZOVÉ SVODIDLO | 1464Záb1096288416 | m | I.OS2 | NEW | OV00.03.2010 | 1.NP
NÁRAZOVÉ SVODIDLO | Půdorys 1.NP | Zámečnické práce | 1.919 | NÁRAZOVÉ SVODIDLO | 1464Záb1096277461 | m | I.OS2 | NEW | OV00.03.2008 | 1.NP
OCHRANA ROHŮ | Půdorys 1.NP | Zámečnické práce | 0.012 | OCHRANA ROHŮ | 1464Záb1096286897 | Kus | II.OS3 | NEW | OV02.03.3008 | 1.NP
OCHRANA ROHŮ | Půdorys 1.NP | Zámečnické práce | 0.012 | OCHRANA ROHŮ | 1464Záb1096286900 | Kus | II.OS3 | NEW | OV02.03.3009 | 1.NP
NÁRAZOVÉ MADLO | Půdorys 1.NP | Zámečnické práce | 3.54 | NÁRAZOVÉ MADLO | 1464Záb1096286917 | m | II.OS1 | NEW | OV02.03.1004 | 1.NP
NÁRAZOVÉ MADLO | Půdorys 1.NP | Zámečnické práce | 2.75 | NÁRAZOVÉ MADLO | 1464Záb1096286926 | m | II.OS1 | NEW | OV02.03.1005 | 1.NP
VERTIKÁLNÍ CHRÁNIČ | Půdorys 1.NP | Zámečnické práce | 0.102 | VERTIKÁLNÍ CHRÁNIČ | 1464Záb1096288573 | Kus | I.OS5 | NEW | OV00.03.5001 | 1.NP
VERTIKÁLNÍ CHRÁNIČ | Půdorys 1.NP | Zámečnické práce | 0.102 | VERTIKÁLNÍ CHRÁNIČ | 1464Záb1096288578 | Kus | I.OS5 | NEW | OV00.03.5002 | 1.NP
VERTIKÁLNÍ CHRÁNIČ | Půdorys 1.NP | Zámečnické práce | 0.102 | VERTIKÁLNÍ CHRÁNIČ | 1464Záb1096288582 | Kus | I.OS5 | NEW | OV00.03.5003 | 1.NP
VERTIKÁLNÍ CHRÁNIČ | Půdorys 1.NP | Zámečnické práce | 0.102 | VERTIKÁLNÍ CHRÁNIČ | 1464Záb1096288585 | Kus | I.OS5 | NEW | OV00.03.5004 | 1.NP
VERTIKÁLNÍ CHRÁNIČ | Půdorys 1.NP | Zámečnické práce | 0.102 | VERTIKÁLNÍ CHRÁNIČ | 1464Záb1096288588 | Kus | I.OS5 | NEW | OV00.03.5005 | 1.NP
VERTIKÁLNÍ CHRÁNIČ | Půdorys 1.NP | Zámečnické práce | 0.102 | VERTIKÁLNÍ CHRÁNIČ | 1464Záb1096288591 | Kus | I.OS5 | NEW | OV00.03.5006 | 1.NP
VERTIKÁLNÍ CHRÁNIČ | Půdorys 1.NP | Zámečnické práce | 0.102 | VERTIKÁLNÍ CHRÁNIČ | 1464Záb1096288594 | Kus | I.OS5 | NEW | OV00.03.5007 | 1.NP
VERTIKÁLNÍ CHRÁNIČ | Půdorys 1.NP | Zámečnické práce | 0.102 | VERTIKÁLNÍ CHRÁNIČ | 1464Záb1096288597 | Kus | I.OS5 | NEW | OV00.03.5008 | 1.NP
VERTIKÁLNÍ CHRÁNIČ | Půdorys 1.NP | Zámečnické práce | 0.102 | VERTIKÁLNÍ CHRÁNIČ | 1464Záb1096288600 | Kus | I.OS5 | NEW | OV00.03.5009 | 1.NP
VERTIKÁLNÍ CHRÁNIČ | Půdorys 1.NP | Zámečnické práce | 0.102 | VERTIKÁLNÍ CHRÁNIČ | 1464Záb1096288603 | Kus | I.OS5 | NEW | OV00.03.5010 | 1.NP
VERTIKÁLNÍ CHRÁNIČ | Půdorys 1.NP | Zámečnické práce | 0.102 | VERTIKÁLNÍ CHRÁNIČ | 1464Záb1096288606 | Kus | I.OS5 | NEW | OV00.03.5011 | 1.NP
VERTIKÁLNÍ CHRÁNIČ | Půdorys 1.NP | Zámečnické práce | 0.102 | VERTIKÁLNÍ CHRÁNIČ | 1464Záb1096288609 | Kus | I.OS5 | NEW | OV00.03.5012 | 1.NP
VERTIKÁLNÍ CHRÁNIČ | Půdorys 1.NP | Zámečnické práce | 0.102 | VERTIKÁLNÍ CHRÁNIČ | 1464Záb1096288612 | Kus | I.OS5 | NEW | OV00.03.5013 | 1.NP
VERTIKÁLNÍ CHRÁNIČ | Půdorys 1.NP | Zámečnické práce | 0.102 | VERTIKÁLNÍ CHRÁNIČ | 1464Záb1096288615 | Kus | I.OS5 | NEW | OV00.03.5014 | 1.NP
VERTIKÁLNÍ CHRÁNIČ | Půdorys 1.NP | Zámečnické práce | 0.102 | VERTIKÁLNÍ CHRÁNIČ | 1464Záb1096288618 | Kus | I.OS5 | NEW | OV00.03.5015 | 1.NP
VERTIKÁLNÍ CHRÁNIČ | Půdorys 1.NP | Zámečnické práce | 0.102 | VERTIKÁLNÍ CHRÁNIČ | 1464Záb1096288621 | Kus | I.OS5 | NEW | OV00.03.5016 | 1.NP
VERTIKÁLNÍ CHRÁNIČ | Půdorys 1.NP | Zámečnické práce | 0.102 | VERTIKÁLNÍ CHRÁNIČ | 1464Záb1096288624 | Kus | I.OS5 | NEW | OV00.03.5017 | 1.NP
VERTIKÁLNÍ CHRÁNIČ | Půdorys 1.NP | Zámečnické práce | 0.102 | VERTIKÁLNÍ CHRÁNIČ | 1464Záb1096288627 | Kus | I.OS5 | NEW | OV00.03.5018 | 1.NP
NÁRAZOVÉ MADLO | Půdorys 1.NP | Zámečnické práce | 4.35 | NÁRAZOVÉ MADLO | 1464Záb1096317233 | m | II.OS1 | NEW | OV02.03.1006 | 1.NP
OCHRANA ROHŮ | Půdorys 1.NP | Zámečnické práce | 0.012 | OCHRANA ROHŮ | 1464Záb1096298694 | Kus | II.OS3 | NEW | OV02.03.3010 | 1.NP
Rail_Path | Půdorys 3.NP | Klempířské práce | 2.025 | Rail_Path | 1652Záb0798445997 | Kus | Zábradlí | EXISTING | Material: TiZn; NEMSOK - Materiál: TiZn
Rail_Path | Půdorys 4.NP | Klempířské práce | 2.025 | Rail_Path | 1752Záb0798431268 | Kus | Zábradlí | EXISTING | Material: TiZn; NEMSOK - Materiál: TiZn

# IfcRoof (16)
NEMSOK - Object Layer Attributes #1, Název_objektu: Vrstva střešní krytiny
Name | In | Object Layer Attributes #1, Práce | Object Layer Attributes #1, Materiál | Object Layer Attributes #1, Allright_Stavebni_dil_ID | Object Layer Attributes #1, Jednotka | Object Layer Attributes #2, Status | Object Layer Attributes #2, Kód prvku | Object Layer Attributes #2, Práce | Object Layer Attributes #2, Materiál | Object Layer Attributes #2, Způsob spojení vrstev | Object Layer Attributes #2, Allright_Stavebni_dil_ID | Object Layer Attributes #2, Jednotka | Object Layer Attributes #2, Název_objektu | Status | VergeLength (m) | Volume (m3) | RidgeLenth (m) | ValleyLength (m) | EavesLength (m) | ArrisLength (m) | GrossArea (m2)
 | Půdorys 2.NP | Krajinné úpravy | II.S2 - KAČÍREK | 1564Stř0000002169 | m2 | Nový | HI01.04.1003 | Pokrývačské práce | ASFALTOVÁ HYDROIZOLACE | Natavený | 1564Stř0000002170 | m2 | Vrstva střešní krytiny | NEW | 54.296 | 1.249 | 26.679 | 2.859 | 23.439 | 0.283 | 10.408
 | Půdorys 2.NP | Krajinné úpravy | II.S1 - SOUVRSTVÍ ZELENÉ STŘECHY | 1564Stř0798476955 | m2 | Nový | HI01.04.0003 | Pokrývačské práce | ASFALTOVÁ HYDROIZOLACE | Natavený | 1564Stř0798476956 | m2 | Vrstva střešní krytiny | NEW | 27.549 | 9.721 | 30.667 | 26.785 | 6.22 | 4.682 | 81.005 | NEMSOK - Object Layer Attributes #1, Staticky nosná konstrukce: no; Object Layer Attributes #2, Staticky nosná konstrukce: no
 | Půdorys 2.NP | Krajinné úpravy | II.S1 - SOUVRSTVÍ ZELENÉ STŘECHY | 1564Stř0798459613 | m2 | Nový | HI01.04.0002 | Pokrývačské práce | ASFALTOVÁ HYDROIZOLACE | Natavený | 1564Stř0798459614 | m2 | Vrstva střešní krytiny | NEW | 8.474 | 6.506 | 29.27 | 20.928 | 4.895 | 0 | 54.215 | NEMSOK - Object Layer Attributes #1, Staticky nosná konstrukce: no; Object Layer Attributes #2, Staticky nosná konstrukce: no
 | Půdorys 2.NP | Krajinné úpravy | II.S2 - KAČÍREK | 1564Stř0000003161 | m2 | Nový | HI01.04.1002 | Pokrývačské práce | ASFALTOVÁ HYDROIZOLACE | Natavený | 1564Stř0000003162 | m2 | Vrstva střešní krytiny | NEW | 16.547 | 0.822 | 27.55 | 2.263 | 24.55 | 0 | 6.847
 | Půdorys 2.NP | Krajinné úpravy | I.S2 - KAČÍREK | 1564Stř0798459398 | m2 | Nový | HI01.04.1001 | Pokrývačské práce | ASFALTOVÁ HYDROIZOLACE | Natavený | 1564Stř0798459399 | m2 | Vrstva střešní krytiny | NEW | 64.469 | 3.19 | 102.64 | 3.395 | 99.24 | 0 | 26.584
 | Půdorys 2.NP | Krajinné úpravy | I.S1 - SOUVRSTVÍ ZELENÉ STŘECHY | 1564Stř0798458981 | m2 | Nový | HI01.04.0001 | Pokrývačské práce | ASFALTOVÁ HYDROIZOLACE | Natavený | 1564Stř0798458982 | m2 | Vrstva střešní krytiny | NEW | 37.833 | 66.236 | 122.03 | 93.616 | 10.836 | 0 | 551.965
 | Půdorys 3.NP | Klempířské práce | STŘECHA + PLECHOVÁ KRYTINA | 1654Stř0000001254 | m2 |  |  |  |  |  |  |  |  | EXISTING | 6.688 | 1.775 | 1.21 | 0 | 1.21 | 0 | 4.046 | Material: STŘECHA + PLECHOVÁ KRYTINA
 | Půdorys 3.NP | Krajinné úpravy | I.S4 - KAČÍREK | 1664Stř0000013433 | m3 | Nový | HI01.05.0001 | Pokrývačské práce | ASFALTOVÁ HYDROIZOLACE | Natavený | 1664Stř0000013434 | m3 | Vrstva střešní krytiny | NEW | 53.554 | 20.554 | 54.487 | 66.172 | 7.915 | 0 | 342.56
 | Půdorys 3.NP | Krajinné úpravy | I.S4 - KAČÍREK | 1664Stř0000000005 | m2 | Nový | HI01.05.0002 | Pokrývačské práce | ASFALTOVÁ HYDROIZOLACE | Natavený | 1664Stř0000000006 | m2 | Vrstva střešní krytiny | NEW | 3.842 | 0.052 | 2.7 | 0 | 2.7 | 0 | 5.186 | NEMSOK - Object Layer Attributes #1, Staticky nosná konstrukce: no; Object Layer Attributes #2, Staticky nosná konstrukce: no
 | Půdorys 5.NP | Klempířské práce | STŘECHA + PLECHOVÁ KRYTINA | 1854Stř0000002226 | m2 |  |  |  |  |  |  |  |  | NEW | 0 | 1.183 | 4.47 | 0 | 4.47 | 0 | 3.945 | NEMSOK - Object Layer Attributes #1, Staticky nosná konstrukce: no; Material: STŘECHA + PLECHOVÁ KRYTINA
 | Půdorys 5.NP | Krajinné úpravy | I.S4 - KAČÍREK | 1864Stř0000004143 | m2 | Nový | HI01.06.0004 | Pokrývačské práce | ASFALTOVÁ HYDROIZOLACE | Natavený | 1864Stř0000004144 | m2 | Vrstva střešní krytiny | NEW | 3.722 | 0.282 | 4.7 | 2.263 | 1.5 | 0 | 4.708
 | Půdorys 5.NP | Krajinné úpravy | I.S4 - KAČÍREK | 1864Stř0000019924 | m2 | Nový | HI01.06.0001 | Pokrývačské práce | ASFALTOVÁ HYDROIZOLACE | Natavený | 1864Stř0000019925 | m2 | Vrstva střešní krytiny | NEW | 86.699 | 34.9 | 96.95 | 80.331 | 24.23 | 0 | 581.666
 | Půdorys 5.NP | Krajinné úpravy | I.S4 - KAČÍREK | 1864Stř0000004005 | m2 | Nový | HI01.06.0002 | Pokrývačské práce | ASFALTOVÁ HYDROIZOLACE | Natavený | 1864Stř0000021694 | m2 | Vrstva střešní krytiny | NEW | 0 | 0.244 | 3.095 | 0 | 6.725 | 0 | 4.062
 | Půdorys 5.NP | Krajinné úpravy | I.S3 - KAČÍREK | 1864Stř0000004102 | m2 | Nový | HI01.06.0003 | Pokrývačské práce | ASFALTOVÁ HYDROIZOLACE | Natavený | 1864Stř0000021703 | m2 | Vrstva střešní krytiny | NEW | 7.879 | 0.372 | 2.36 | 0 | 2.36 | 0 | 9.297
 | Půdorys 6.NP | Krajinné úpravy | I.S4 - KAČÍREK | 1964Stř0000003369 | m2 | Nový | HI01.07.0001 | Pokrývačské práce | ASFALTOVÁ HYDROIZOLACE | Natavený | 1964Stř0000003370 | m2 | Vrstva střešní krytiny | NEW | 34.676 | 15.368 | 46.084 | 42.334 | 1.592 | 0 | 256.131
 | Půdorys střechy | Krajinné úpravy | I.S4 - KAČÍREK | 2481Stř0000000694 | m2 | Nový | HI01.08.0001 | Pokrývačské práce | ASFALTOVÁ HYDROIZOLACE | Natavený | 2481Stř0000000695 | m2 | Vrstva střešní krytiny | NEW | 24.411 | 4.736 | 14.16 | 11.161 | 1.1 | 0 | 78.938

# IfcSlab (566)
Name | In | PredefinedType | Material | 2D interakce | Krátký_text | Práce | Materiál | Allright_Stavebni_dil_ID | Jednotka | Název_objektu | Status | LoadBearing | GrossArea (m2) | Depth (m) | NetArea (m2) | GrossVolume (m3) | Perimeter (m) | NetVolume (m3) | Length (m) | Width (m)
 | Půdorys 1.PP | FLOOR | PREFA ŽB ENERGOKANÁL | yes | Betonová deska (Atribut objektu!) | Betonářské práce | PREFA ŽB ENERGOKANÁL | 1302Des0798451470 | m3 | Deska | EXISTING | no | 5.756 | 3.71 | 5.756 | 0.576 | 10.53 | 0.576 | 1.551 | 0.1
 | Půdorys 1.PP | FLOOR | PREFA ŽB ENERGOKANÁL | yes | Betonová deska (Atribut objektu!) | Betonářské práce | PREFA ŽB ENERGOKANÁL | 1302Des0798451475 | m3 | Deska | EXISTING | no | 5.942 | 3.71 | 5.942 | 0.594 | 10.63 | 0.594 | 1.601 | 0.1
 | Půdorys 1.PP | FLOOR | ZELEZOBETONOVÁ KCE | yes | Betonová deska (Atribut objektu!) | Betonářské práce | ZELEZOBETONOVÁ KCE | 1302Des0798453551 | m3 | Deska | EXISTING | no | 12.095 | 1.739 | 10.955 | 2.419 | 17.387 | 2.191 | 6.954 | 0.2
 | Půdorys 1.PP | FLOOR | ZELEZOBETONOVÁ KCE | yes | Betonová deska (Atribut objektu!) | Betonářské práce | ZELEZOBETONOVÁ KCE | 1304Des0000000026 | m3 | Deska | EXISTING | no | 5.756 | 3.71 | 5.756 | 0.576 | 10.53 | 0.576 | 1.551 | 0.1
 | Půdorys 1.PP | FLOOR | ZELEZOBETONOVÁ KCE | yes | Betonová deska (Atribut objektu!) | Betonářské práce | ZELEZOBETONOVÁ KCE | 1304Des0000000028 | m3 | Deska | EXISTING | no | 5.942 | 3.71 | 5.942 | 0.594 | 10.63 | 0.594 | 1.601 | 0.1
 | Půdorys 1.PP | FLOOR | ZELEZOBETONOVÁ KCE | yes | Betonová deska (Atribut objektu!) | Betonářské práce | ZELEZOBETONOVÁ KCE | 1304Des0000000017 | m3 | Deska | EXISTING | no | 12.095 | 1.739 | 10.97 | 2.419 | 17.387 | 2.194 | 6.954 | 0.2
 | Základy | BASESLAB |  | yes |  | Betonářské práce |  | 0877ZDe0000000256 | m3 | Základová deska | EXISTING | no | 35.84 | 5.12 | 35.84 | 14.336 | 24.24 | 14.336 | 7 | 0.4
 | Základy | BASESLAB | ŽB ZÁKLADOVÁ DESKA | yes |  | Betonářské práce | ŽB ZÁKLADOVÁ DESKA | 0881ZDe0000000208 | m3 | Základová deska | NEW | yes | 139.619 | 9.327 | 139.619 | 41.886 | 54.59 | 41.886 | 14.97 | 0.3 | NEMSOK - Kód prvku: ZD02.01.0001; Třída pevnosti ocele: B500B; Stupeň vyztužení: 120; Třída pevnosti betonu: C25/30-XC1; Krytí výztuže: 25mm
Podkladní beton | Základy | FLOOR | BETONOVÁ KCE | yes | Betonová deska (Atribut objektu!) | Betonářské práce | BETONOVÁ KCE | 0890Des0000000002 | m3 | Deska | NEW | no | 110.9 | 3.195 | 110.9 | 11.09 | 73.33 | 11.09 | 34.71 | 0.1 | NEMSOK - Kód prvku: DZ01.01.0002; Stupeň vyztužení: 0; Třída pevnosti betonu: C12/15-X0; Označení: Podkladní beton
Podkladní beton | Základy | FLOOR | BETONOVÁ KCE | yes | Betonová deska (Atribut objektu!) | Betonářské práce | BETONOVÁ KCE | 0890Des0000000041 | m3 | Deska | NEW | no | 51.046 | 1.8 | 51.046 | 2.552 | 130.36 | 2.552 | 28.359 | 0.05 | NEMSOK - Kód prvku: DZ01.01.0001; Stupeň vyztužení: 0; Třída pevnosti betonu: C12/15-X0; Označení: Podkladní beton
 | Půdorys 1.PP | FLOOR | ZELEZOBETONOVÁ KCE | yes | Betonová deska (Atribut objektu!) | Betonářské práce | ZELEZOBETONOVÁ KCE | 1352Des0798466970 | m3 | Deska | EXISTING | no | 2.4 | 2.4 | 2.4 | 0.432 | 6.8 | 0.432 | 1 | 0.18
 | Půdorys 1.PP | FLOOR | ZELEZOBETONOVÁ KCE | yes | Betonová deska (Atribut objektu!) | Betonářské práce | ZELEZOBETONOVÁ KCE | 1352Des0798466969 | m3 | Deska | EXISTING | no | 2.4 | 2.4 | 2.4 | 0.432 | 6.8 | 0.432 | 1 | 0.18
 | Půdorys 1.PP | FLOOR | ZELEZOBETONOVÁ KCE | yes | Betonová deska (Atribut objektu!) | Betonářské práce | ZELEZOBETONOVÁ KCE | 1352Des0798480439 | m3 | Deska | EXISTING | no | 1 | 1 | 1 | 0.2 | 4 | 0.2 | 1 | 0.2
 | Půdorys 1.PP | FLOOR | PREFA ŽB ENERGOKANÁL | yes | Betonová deska (Atribut objektu!) | Betonářské práce | PREFA ŽB ENERGOKANÁL | 1352Des0798467780 | m3 | Deska | EXISTING | no | 13.815 | 8.905 | 13.815 | 1.382 | 20.929 | 1.382 | 1.551 | 0.1
 | Půdorys 1.PP | FLOOR | PREFA ŽB ENERGOKANÁL | yes | Betonová deska (Atribut objektu!) | Betonářské práce | PREFA ŽB ENERGOKANÁL | 1352Des0798467783 | m3 | Deska | EXISTING | no | 14.261 | 1.601 | 14.261 | 1.426 | 21.029 | 1.426 | 8.905 | 0.1
 | Půdorys 1.PP | FLOOR | ZELEZOBETONOVÁ KCE | yes | Betonová deska (Atribut objektu!) | Betonářské práce | ZELEZOBETONOVÁ KCE | 1352Des0000004705 | m3 | Deska | EXISTING | no | 1.26 | 2.4 | 1.068 | 0.227 | 5.85 | 0.192 | 0.525 | 0.18
 | Půdorys 1.PP | FLOOR | ZELEZOBETONOVÁ KCE | yes | Betonová deska (Atribut objektu!) | Betonářské práce | ZELEZOBETONOVÁ KCE | 1352Des0000004700 | m3 | Deska | EXISTING | no | 1.26 | 2.4 | 1.008 | 0.227 | 5.85 | 0.181 | 0.525 | 0.18
 | Půdorys 1.PP | FLOOR | PZD | yes | Betonová deska (Atribut objektu!) | Betonářské práce | PZD | 1354Des0000000580 | m3 | Deska | EXISTING | yes | 12.98 | 5.9 | 12.98 | 3.245 | 16.2 | 3.245 | 2.2 | 0.25
 | Půdorys 1.PP | FLOOR | PZD | yes | Betonová deska (Atribut objektu!) | Betonářské práce | PZD | 1354Des0000000049 | m3 | Deska | EXISTING | yes | 8.75 | 3.5 | 8.75 | 2.187 | 12 | 2.094 | 2.5 | 0.25
 | Půdorys 1.PP | FLOOR | RZT | yes | Betonová deska (Atribut objektu!) | Betonářské práce | RZT | 1354Des0000000539 | m3 | Deska | EXISTING | yes | 8.4 | 6 | 8.4 | 2.1 | 14.8 | 2.1 | 1.4 | 0.25
 | Půdorys 1.PP | FLOOR | RZT | yes | Betonová deska (Atribut objektu!) | Betonářské práce | RZT | 1354Des0000000534 | m3 | Deska | EXISTING | yes | 8.4 | 6 | 8.4 | 2.1 | 14.8 | 2.1 | 1.4 | 0.25
 | Půdorys 1.PP | FLOOR | DZH | yes | Betonová deska (Atribut objektu!) | Betonářské práce | DZH | 1354Des0000000683 | m3 | Deska | EXISTING | yes | 5.44 | 3.4 | 5.44 | 1.36 | 10 | 1.36 | 1.6 | 0.25
 | Půdorys 1.PP | FLOOR | RZT | yes | Betonová deska (Atribut objektu!) | Betonářské práce | RZT | 1354Des0000000574 | m3 | Deska | EXISTING | yes | 8.26 | 5.9 | 8.26 | 2.065 | 14.6 | 2.065 | 1.4 | 0.25
 | Půdorys 1.PP | FLOOR | VĚNEC | yes | Betonová deska (Atribut objektu!) | Betonářské práce | VĚNEC | 1354Des0000001194 | m3 | Deska | EXISTING | yes | 7.169 | 1.07 | 7.169 | 1.792 | 15.54 | 1.792 | 6.7 | 0.25
 | Půdorys 1.PP | FLOOR | RZT | yes | Betonová deska (Atribut objektu!) | Betonářské práce | RZT | 1354Des0000000577 | m3 | Deska | EXISTING | yes | 19.068 | 14.43 | 19.068 | 4.767 | 31.66 | 4.767 | 1.321 | 0.25
 | Půdorys 1.PP | FLOOR | PZD | yes | Betonová deska (Atribut objektu!) | Betonářské práce | PZD | 1354Des0000000696 | m3 | Deska | EXISTING | yes | 31.746 | 2.2 | 31.596 | 7.937 | 33.26 | 7.899 | 14.43 | 0.25
 | Půdorys 1.PP | FLOOR | PZD | yes | Betonová deska (Atribut objektu!) | Betonářské práce | PZD | 1354Des0000000658 | m3 | Deska | EXISTING | yes | 62.66 | 2.8 | 61.85 | 15.665 | 43.5 | 15.463 | 22.379 | 0.25
 | Půdorys 1.PP | FLOOR | PZD | yes | Betonová deska (Atribut objektu!) | Betonářské práce | PZD | 1354Des0000000270 | m3 | Deska | EXISTING | yes | 66.24 | 4.6 | 65.555 | 16.56 | 38 | 16.389 | 14.4 | 0.25
 | Půdorys 1.PP | FLOOR | RZT | yes | Betonová deska (Atribut objektu!) | Betonářské práce | RZT | 1354Des0000000261 | m3 | Deska | EXISTING | yes | 20.16 | 14.4 | 20.16 | 5.04 | 31.6 | 5.04 | 1.4 | 0.25
 | Půdorys 1.PP | FLOOR | PZD | yes | Betonová deska (Atribut objektu!) | Betonářské práce | PZD | 1354Des0000000058 | m3 | Deska | EXISTING | yes | 21.195 | 2.7 | 21.126 | 2.12 | 21.1 | 2.113 | 7.85 | 0.1
 | Půdorys 1.PP | FLOOR | PZD | yes | Betonová deska (Atribut objektu!) | Betonářské práce | PZD | 1354Des0000000045 | m3 | Deska | EXISTING | yes | 6.93 | 3.3 | 6.65 | 0.693 | 10.8 | 0.665 | 2.1 | 0.1
 | Půdorys 1.PP | FLOOR | RZT | yes | Betonová deska (Atribut objektu!) | Betonářské práce | RZT | 1354Des0000000272 | m3 | Deska | EXISTING | yes | 20.16 | 14.4 | 20.16 | 5.04 | 31.6 | 5.04 | 1.4 | 0.25
 | Půdorys 1.PP | FLOOR | RZT | yes | Betonová deska (Atribut objektu!) | Betonářské práce | RZT | 1354Des0000000573 | m3 | Deska | EXISTING | yes | 37.1 | 26.5 | 37.1 | 9.275 | 55.8 | 9.275 | 1.4 | 0.25
 | Půdorys 1.PP | FLOOR | RZT | yes | Betonová deska (Atribut objektu!) | Betonářské práce | RZT | 1354Des0000000917 | m3 | Deska | EXISTING | yes | 8.68 | 6.2 | 8.68 | 2.17 | 15.2 | 2.17 | 1.4 | 0.25
 | Půdorys 1.PP | FLOOR | RZT | yes | Betonová deska (Atribut objektu!) | Betonářské práce | RZT | 1354Des0000000918 | m3 | Deska | EXISTING | yes | 3.64 | 2.6 | 3.64 | 0.91 | 8 | 0.91 | 1.4 | 0.25
 | Půdorys 1.PP | FLOOR | PZD | yes | Betonová deska (Atribut objektu!) | Betonářské práce | PZD | 1354Des0000000587 | m3 | Deska | EXISTING | yes | 58.3 | 2.2 | 57.52 | 14.575 | 57.4 | 14.38 | 26.5 | 0.25
 | Půdorys 1.PP | FLOOR | RZT | yes | Betonová deska (Atribut objektu!) | Betonářské práce | RZT | 1354Des0000000548 | m3 | Deska | EXISTING | yes | 16.8 | 12 | 16.8 | 4.2 | 26.8 | 4.2 | 1.4 | 0.25
 | Půdorys 1.PP | FLOOR | RZT | yes | Betonová deska (Atribut objektu!) | Betonářské práce | RZT | 1354Des0000000571 | m3 | Deska | EXISTING | yes | 37.1 | 26.5 | 37.1 | 9.275 | 55.8 | 9.275 | 1.4 | 0.25
 | Půdorys 1.PP | FLOOR | RZT | yes | Betonová deska (Atribut objektu!) | Betonářské práce | RZT | 1354Des0000000533 | m3 | Deska | EXISTING | yes | 37.1 | 26.5 | 37.1 | 9.275 | 55.8 | 9.275 | 1.4 | 0.25
 | Půdorys 1.PP | FLOOR | PZD | yes | Betonová deska (Atribut objektu!) | Betonářské práce | PZD | 1354Des0000000251 | m3 | Deska | EXISTING | yes | 66.24 | 4.6 | 65.61 | 16.56 | 38 | 16.403 | 14.4 | 0.25
 | Půdorys 1.PP | FLOOR | PZD | yes | Betonová deska (Atribut objektu!) | Betonářské práce | PZD | 1354Des0000000258 | m3 | Deska | EXISTING | yes | 66.24 | 4.6 | 65.54 | 16.56 | 38 | 16.385 | 14.4 | 0.25
 | Půdorys 1.PP | FLOOR | PZD | yes | Betonová deska (Atribut objektu!) | Betonářské práce | PZD | 1354Des0000000234 | m3 | Deska | EXISTING | yes | 66.24 | 4.6 | 65.811 | 16.56 | 38 | 16.453 | 14.4 | 0.25
 | Půdorys 1.PP | FLOOR | RZT | yes | Betonová deska (Atribut objektu!) | Betonářské práce | RZT | 1354Des0000000239 | m3 | Deska | EXISTING | yes | 20.16 | 14.4 | 20.142 | 5.04 | 31.6 | 5.036 | 1.4 | 0.25
 | Půdorys 1.PP | FLOOR | RZT | yes | Betonová deska (Atribut objektu!) | Betonářské práce | RZT | 1354Des0000000243 | m3 | Deska | EXISTING | yes | 20.16 | 14.4 | 20.142 | 5.04 | 31.6 | 5.036 | 1.4 | 0.25
 | Půdorys 1.PP | FLOOR | RZT | yes | Betonová deska (Atribut objektu!) | Betonářské práce | RZT | 1354Des0000000532 | m3 | Deska | EXISTING | yes | 35.28 | 25.2 | 35.262 | 8.82 | 53.2 | 8.816 | 1.4 | 0.25
 | Půdorys 1.PP | FLOOR | RZT | yes | Betonová deska (Atribut objektu!) | Betonářské práce | RZT | 1354Des0000000228 | m3 | Deska | EXISTING | yes | 20.16 | 14.4 | 20.142 | 5.04 | 31.6 | 5.036 | 1.4 | 0.25
 | Půdorys 1.PP | FLOOR | ZELEZOBETONOVÁ KCE | yes | Betonová deska (Atribut objektu!) | Betonářské práce | ZELEZOBETONOVÁ KCE | 1354Des0000002470 | m3 | Deska | EXISTING | no | 13.815 | 8.905 | 13.815 | 1.382 | 20.929 | 1.382 | 1.551 | 0.1
 | Půdorys 1.PP | FLOOR | ZELEZOBETONOVÁ KCE | yes | Betonová deska (Atribut objektu!) | Betonářské práce | ZELEZOBETONOVÁ KCE | 1354Des0000002468 | m3 | Deska | EXISTING | no | 14.261 | 1.601 | 14.261 | 1.426 | 21.029 | 1.426 | 8.905 | 0.1
 | Půdorys 1.PP | FLOOR | PZD | yes | Betonová deska (Atribut objektu!) | Betonářské práce | PZD | 1354Des0000000712 | m3 | Deska | EXISTING | yes | 8.277 | 2.67 | 8.217 | 2.069 | 11.54 | 2.054 | 3.1 | 0.25
 | Půdorys 1.PP | FLOOR | RZT | yes | Betonová deska (Atribut objektu!) | Betonářské práce | RZT | 1354Des0000000531 | m3 | Deska | EXISTING | yes | 35.28 | 25.2 | 35.237 | 8.82 | 53.2 | 8.809 | 1.4 | 0.25
 | Půdorys 1.PP | FLOOR | PZD | yes | Betonová deska (Atribut objektu!) | Betonářské práce | PZD | 1354Des0000000624 | m3 | Deska | EXISTING | yes | 99.12 | 25.2 | 98.224 | 24.78 | 89.2 | 24.556 | 3.933 | 0.25
 | Půdorys 1.PP | FLOOR | RZT | yes | Betonová deska (Atribut objektu!) | Betonářské práce | RZT | 1354Des0000000572 | m3 | Deska | EXISTING | yes | 37.1 | 26.5 | 37.074 | 9.275 | 55.8 | 9.269 | 1.4 | 0.25
 | Půdorys 1.PP | FLOOR | PZD | yes | Betonová deska (Atribut objektu!) | Betonářské práce | PZD | 1354Des0000000921 | m3 | Deska | EXISTING | yes | 109.58 | 4.6 | 105.826 | 27.395 | 85.4 | 26.457 | 23.822 | 0.25
 | Půdorys 1.PP | FLOOR | PZD | yes | Betonová deska (Atribut objektu!) | Betonářské práce | PZD | 1354Des0000000601 | m3 | Deska | EXISTING | yes | 105.1 | 26.5 | 103.86 | 26.275 | 89 | 25.965 | 3.966 | 0.25
 | Půdorys 1.PP | FLOOR | ZELEZOBETONOVÁ KCE | yes | Betonová deska (Atribut objektu!) | Betonářské práce | ZELEZOBETONOVÁ KCE | 1354Des0000002457 | m3 | Deska | EXISTING | no | 80.521 | 6.699 | 80.486 | 24.156 | 39.14 | 24.146 | 12.02 | 0.3
 | Půdorys 1.PP | FLOOR | PZD | yes | Betonová deska (Atribut objektu!) | Betonářské práce | PZD | 1354Des0000000651 | m3 | Deska | EXISTING | yes | 55.44 | 2.2 | 54.874 | 13.86 | 54.8 | 13.718 | 25.2 | 0.25
 | Půdorys 1.PP | FLOOR | Kuchyňská deska | yes | Kuchyňská deska | Truhlářské práce | Kuchyňská deska | 1364Des0798480877 | m2 | Deska | NEW |  | 0.749 | 1.8 | 0.752 | 0.022 | 7.81 | 0.022 | 0.416 | 0.03 | NEMSOK - Kód prvku: TV00.02.0001; Číslo místnosti: -1.35; Podlaží: 1.PP
 | Půdorys 1.PP | FLOOR | Kuchyňská deska | yes | Kuchyňská deska | Truhlářské práce | Kuchyňská deska | 1364Des0798505188 | m2 | Deska | NEW |  | 0.749 | 1.8 | 0.752 | 0.022 | 7.81 | 0.022 | 0.416 | 0.03 | NEMSOK - Kód prvku: TV00.02.0002; Číslo místnosti: -1.36; Podlaží: 1.PP
 | Půdorys 1.PP | FLOOR | Kuchyňská deska | yes | Kuchyňská deska | Truhlářské práce | Kuchyňská deska | 1364Des0798505203 | m2 | Deska | NEW |  | 0.749 | 1.8 | 0.752 | 0.022 | 7.81 | 0.022 | 0.416 | 0.03 | NEMSOK - Kód prvku: TV00.02.0002; Číslo místnosti: -1.37; Podlaží: 1.PP
 | Půdorys 1.PP | FLOOR | Kuchyňská deska | yes | Kuchyňská deska | Truhlářské práce | Kuchyňská deska | 1364Des0798505250 | m2 | Deska | NEW |  | 0.749 | 1.8 | 0.752 | 0.022 | 7.81 | 0.022 | 0.416 | 0.03 | NEMSOK - Kód prvku: TV00.02.0002; Číslo místnosti: -1.49; Podlaží: 1.PP
 | Půdorys 1.PP | FLOOR | Kuchyňská deska | yes | Kuchyňská deska | Truhlářské práce | Kuchyňská deska | 1364Des0798505272 | m2 | Deska | NEW |  | 0.749 | 1.8 | 0.752 | 0.022 | 7.81 | 0.022 | 0.416 | 0.03 | NEMSOK - Kód prvku: TV00.02.0002; Číslo místnosti: -1.39; Podlaží: 1.PP
 | Půdorys 1.PP | FLOOR | Kuchyňská deska | yes | 0 | Zednické práce | Kuchyňská deska | 1364Des0798495705 | m2 | Deska | NEW | no | 1.452 | 2.4 | 1.456 | 0.044 | 9.514 | 0.044 | 0.605 | 0.03 | NEMSOK - Kód prvku: TV00.02.0003; Číslo místnosti: -1.62; Podlaží: 1.PP
 | Půdorys 1.PP | FLOOR | ZELEZOBETONOVÁ KCE | yes | Betonová deska (Atribut objektu!) | Betonářské práce | ZELEZOBETONOVÁ KCE | 1364Des0798495177 | m3 | Deska | NEW | yes | 2.84 | 1.9 | 2.841 | 0.568 | 6.79 | 0.568 | 1.495 | 0.2 | NEMSOK - Kód prvku: ZD02.02.0004; Třída pevnosti ocele: B500B; Stupeň vyztužení: 120; Třída pevnosti betonu: C25/30-XC1; Krytí výztuže: 25mm; Statická funkce: Ano
 | Půdorys 1.PP | BASESLAB | ŽB ZÁKLADOVÁ DESKA | yes |  | Betonářské práce | ŽB ZÁKLADOVÁ DESKA | 1364ZDe0798490809 | m3 | Základová deska | NEW | yes | 113.516 | 7.194 | 112.581 | 22.703 | 55.75 | 22.516 | 15.78 | 0.2 | NEMSOK - Kód prvku: ZD02.02.0003; Třída pevnosti ocele: B500B; Stupeň vyztužení: 120; Třída pevnosti betonu: C25/30-XC1; Krytí výztuže: 25mm; Statická funkce: Ano
 | Půdorys 1.PP | BASESLAB | ŽB ZÁKLADOVÁ DESKA | yes |  | Betonářské práce | ŽB ZÁKLADOVÁ DESKA | 1364ZDe0798506401 | m3 | Základová deska | NEW | yes | 138.845 | 9.655 | 138.847 | 27.769 | 55.7 | 27.769 | 14.38 | 0.2 | NEMSOK - Kód prvku: ZD02.02.0002; Třída pevnosti ocele: B500B; Stupeň vyztužení: 120; Třída pevnosti betonu: C25/30-XC1; Krytí výztuže: 25mm; Statická funkce: Ano
 | Půdorys 1.PP | BASESLAB | ŽB ZÁKLADOVÁ DESKA | yes |  | Betonářské práce | ŽB ZÁKLADOVÁ DESKA | 1364ZDe0798507679 | m3 | Základová deska | NEW | yes | 212.92 | 12.167 | 212.921 | 42.584 | 64.86 | 42.581 | 17.5 | 0.2 | NEMSOK - Kód prvku: ZD02.02.0001; Třída pevnosti ocele: B500B; Stupeň vyztužení: 120; Třída pevnosti betonu: C25/30-XC1; Krytí výztuže: 25mm; Statická funkce: Ano
DNO ANGLICKÉHO DVORKU | Půdorys 1.PP | FLOOR | ANGLICKÝ DVOREK SE DNEM POCHOZÍ | yes | Betonová deska (Atribut objektu!) | Betonářské práce | ANGLICKÝ DVOREK SE DNEM POCHOZÍ | 1364Des0798473514 | Kus | I.AD1 | NEW | no | 1.5 | 1.41 | 1.5 | 0.15 | 5.58 | 0.15 | 1.064 | 0.1 | NEMSOK - Kód prvku: OV00.02.0001; Označení: DNO ANGLICKÉHO DVORKU; Podlaží: 1.PP; Statická funkce: Ne
DNO ANGLICKÉHO DVORKU | Půdorys 1.PP | FLOOR | ANGLICKÝ DVOREK SE DNEM POCHOZÍ | yes | Betonová deska (Atribut objektu!) | Betonářské práce | ANGLICKÝ DVOREK SE DNEM POCHOZÍ | 1364Des0798491587 | Kus | I.AD1 | NEW | no | 1.5 | 1.41 | 1.5 | 0.15 | 5.58 | 0.15 | 1.064 | 0.1 | NEMSOK - Kód prvku: OV00.02.0001; Označení: DNO ANGLICKÉHO DVORKU; Podlaží: 1.PP; Statická funkce: Ne
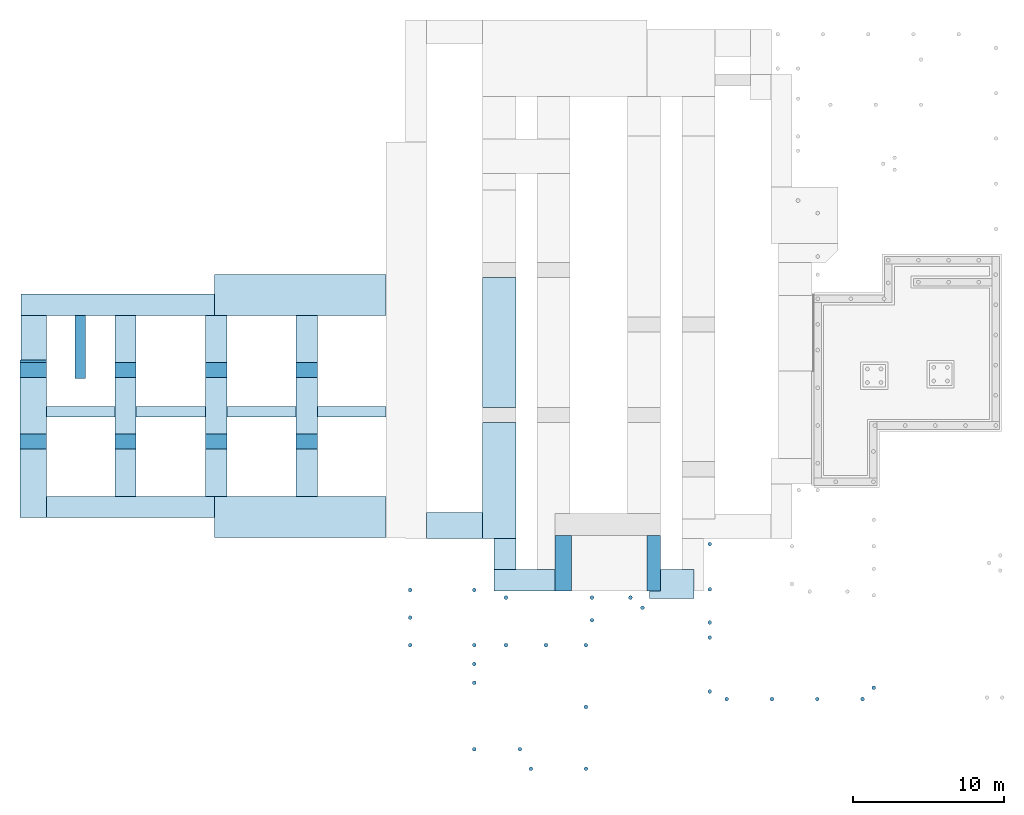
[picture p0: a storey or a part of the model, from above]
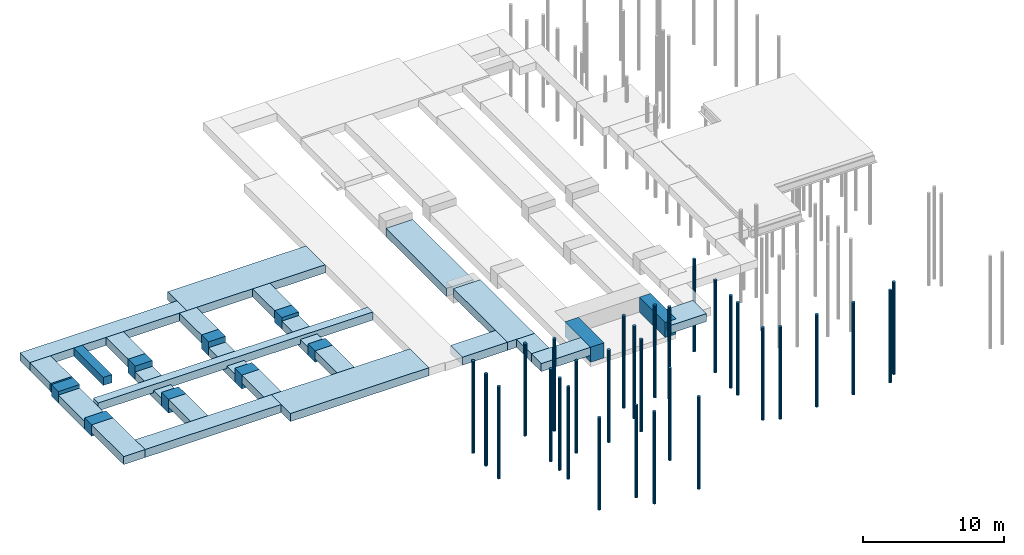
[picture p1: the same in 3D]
Properties of the parts of a building model (IFC4), part 21 of 45

# IfcSlab (566)
Name | In | PredefinedType | Material | 2D interakce | Krátký_text | Práce | Materiál | Allright_Stavebni_dil_ID | Jednotka | Název_objektu | Status | LoadBearing | GrossArea (m2) | Depth (m) | NetArea (m2) | GrossVolume (m3) | Perimeter (m) | NetVolume (m3) | Length (m) | Width (m)
DNO ANGLICKÉHO DVORKU | Půdorys 1.PP | FLOOR | ANGLICKÝ DVOREK SE DNEM POCHOZÍ | yes | Betonová deska (Atribut objektu!) | Betonářské práce | ANGLICKÝ DVOREK SE DNEM POCHOZÍ | 1364Des0798495696 | Kus | I.AD6 | NEW | no | 0.766 | 1.16 | 0.766 | 0.077 | 4.28 | 0.077 | 0.661 | 0.1 | NEMSOK - Kód prvku: OV00.02.0001; Označení: DNO ANGLICKÉHO DVORKU; Podlaží: 1.PP; Statická funkce: Ne
DNO ANGLICKÉHO DVORKU | Půdorys 1.PP | FLOOR | ANGLICKÝ DVOREK SE DNEM POCHOZÍ | yes | Betonová deska (Atribut objektu!) | Betonářské práce | ANGLICKÝ DVOREK SE DNEM POCHOZÍ | 1364Des0798495831 | Kus | I.AD4 | NEW | no | 2.364 | 2.21 | 2.364 | 0.236 | 7.18 | 0.236 | 1.07 | 0.1 | NEMSOK - Kód prvku: OV00.02.0001; Označení: DNO ANGLICKÉHO DVORKU; Podlaží: 1.PP; Statická funkce: Ne
DNO ANGLICKÉHO DVORKU | Půdorys 1.PP | FLOOR | ANGLICKÝ DVOREK SE DNEM POCHOZÍ | yes | Betonová deska (Atribut objektu!) | Betonářské práce | ANGLICKÝ DVOREK SE DNEM POCHOZÍ | 1364Des0798495889 | Kus | I.AD5 | NEW | no | 2.364 | 2.21 | 2.364 | 0.236 | 7.18 | 0.236 | 1.07 | 0.1 | NEMSOK - Kód prvku: OV00.02.0001; Označení: DNO ANGLICKÉHO DVORKU; Podlaží: 1.PP; Statická funkce: Ne
DNO ANGLICKÉHO DVORKU | Půdorys 1.PP | FLOOR | ANGLICKÝ DVOREK SE DNEM POCHOZÍ | yes | Betonová deska (Atribut objektu!) | Betonářské práce | ANGLICKÝ DVOREK SE DNEM POCHOZÍ | 1364Des0798499920 | Kus | I.AD3 | NEW | no | 0.766 | 1.16 | 0.766 | 0.077 | 4.28 | 0.077 | 0.661 | 0.1 | NEMSOK - Kód prvku: OV00.02.0001; Označení: DNO ANGLICKÉHO DVORKU; Podlaží: 1.PP; Statická funkce: Ne
 | Půdorys 1.PP | FLOOR | ZELEZOBETONOVÁ KCE | yes | Betonová deska (Atribut objektu!) | Betonářské práce | ZELEZOBETONOVÁ KCE | 1364Des0798526870 | m3 | Deska | NEW | no | 0.306 | 0.255 | 0.306 | 0.046 | 2.91 | 0.046 | 1.2 | 0.15 | NEMSOK - Kód prvku: SK01.02.0001; Třída pevnosti ocele: B500B; Stupeň vyztužení: 150; Třída pevnosti betonu: C25/30-XC1; Krytí výztuže: 25mm; Podlaží: 1.PP; Statická funkce: Ne; Požární odolnost: A
 | Půdorys 1.PP | FLOOR | ZELEZOBETONOVÁ KCE | yes | Betonová deska (Atribut objektu!) | Betonářské práce | ZELEZOBETONOVÁ KCE | 1364Des0798526889 | m3 | Deska | NEW | no | 0.306 | 0.255 | 0.306 | 0.046 | 2.91 | 0.046 | 1.2 | 0.15 | NEMSOK - Kód prvku: SK01.02.0002; Třída pevnosti ocele: B500B; Stupeň vyztužení: 150; Třída pevnosti betonu: C25/30-XC1; Krytí výztuže: 25mm; Podlaží: 1.PP; Statická funkce: Ne; Požární odolnost: A
 | Půdorys 1.PP | FLOOR | ZELEZOBETONOVÁ KCE | yes | Betonová deska (Atribut objektu!) | Betonářské práce | ZELEZOBETONOVÁ KCE | 1366Des0000000002 | m3 | Deska | NEW | no | 2.841 | 1.9 | 1.491 | 0.568 | 6.79 | 0.298 | 1.495 | 0.2 | NEMSOK - Kód prvku: SK01.02.0004; Stupeň vyztužení: 0; Podlaží: 1.PP; Požární odolnost: A
 | Půdorys 1.PP | FLOOR | ZELEZOBETONOVÁ KCE | yes | Betonová deska (Atribut objektu!) | Betonářské práce | ZELEZOBETONOVÁ KCE | 1366Des0000000014 | m3 | Deska | NEW | no | 138.701 | 9.265 | 138.014 | 34.675 | 54.08 | 34.503 | 14.97 | 0.25 | NEMSOK - Kód prvku: SK01.02.0003; Stupeň vyztužení: 0; Podlaží: 1.PP; Požární odolnost: A
 | Půdorys 1.PP | FLOOR | Demontáž +montáž kazetového podh | yes | Stávající kazetový podhled | Suché stavební práce | Demontáž +montáž kazetového podh | 1368Des0000000902 | m3 | Deska | EXISTING | no | 3.03 | 0.6 | 3.03 | 0.152 | 11.3 | 0.152 | 5.05 | 0.05
 | Půdorys 1.PP | FLOOR | Demontáž +montáž kazetového podh | yes | Stávající kazetový podhled | Suché stavební práce | Demontáž +montáž kazetového podh | 1368Des0000000905 | m3 | Deska | EXISTING | no | 1.1 | 0.4 | 1.1 | 0.055 | 6.3 | 0.055 | 2.75 | 0.05
 | Půdorys 1.PP | FLOOR | Demontáž +montáž podhledu FEAL | yes | Stávající FEAL podhled | Suché stavební práce | Demontáž +montáž podhledu FEAL | 1368Des0000000908 | m3 | Deska | EXISTING |  | 0.57 | 0.3 | 0.57 | 0.029 | 4.4 | 0.029 | 1.9 | 0.05
 | Půdorys 1.PP | FLOOR | Demontáž +montáž podhledu FEAL | yes | Stávající FEAL podhled | Suché stavební práce | Demontáž +montáž podhledu FEAL | 1368Des0000000911 | m3 | Deska | EXISTING |  | 0.798 | 1.45 | 0.798 | 0.04 | 4 | 0.04 | 0.55 | 0.05
 | Půdorys 1.PP | FLOOR | Demontáž +montáž podhledu FEAL | yes | Stávající FEAL podhled | Suché stavební práce | Demontáž +montáž podhledu FEAL | 1368Des0000000946 | m3 | Deska | EXISTING | no | 2 | 1.4 | 2 | 0.1 | 9 | 0.1 | 1.429 | 0.05
 | Půdorys 1.PP | FLOOR | Demontáž +montáž kazetového podh | yes | Stávající kazetový podhled | Suché stavební práce | Demontáž +montáž kazetového podh | 1368Des0000001009 | m3 | Deska | EXISTING | no | 0.66 | 1.1 | 0.66 | 0.033 | 3.4 | 0.033 | 0.6 | 0.05
 | Půdorys 1.PP | FLOOR | Demontáž +montáž kazetového podh | yes | Stávající kazetový podhled | Suché stavební práce | Demontáž +montáž kazetového podh | 1368Des0000001531 | m3 | Deska | EXISTING | no | 3.96 | 9.9 | 3.96 | 0.198 | 20.6 | 0.198 | 0.4 | 0.05
 | Půdorys 1.PP | FLOOR | Demontáž +montáž kazetového podh | yes | Stávající kazetový podhled | Suché stavební práce | Demontáž +montáž kazetového podh | 1368Des0000001534 | m3 | Deska | EXISTING | no | 1.484 | 2.911 | 1.484 | 0.074 | 8.221 | 0.074 | 0.51 | 0.05
 | Půdorys 1.PP | FLOOR | Demontáž +montáž kazetového podh | yes | Stávající kazetový podhled | Suché stavební práce | Demontáž +montáž kazetového podh | 1368Des0000001537 | m3 | Deska | EXISTING | no | 2.7 | 5.4 | 2.7 | 0.135 | 11.8 | 0.135 | 0.5 | 0.05
 | Půdorys 1.PP | FLOOR | Demontáž +montáž podhledu FEAL | yes | Stávající FEAL podhled | Suché stavební práce | Demontáž +montáž podhledu FEAL | 1368Des0000001540 | m3 | Deska | EXISTING | no | 1.063 | 2.125 | 1.063 | 0.053 | 5.25 | 0.053 | 0.5 | 0.05
 | Půdorys 1.PP | FLOOR | Demontáž +montáž kazetového podh | yes | Stávající kazetový podhled | Suché stavební práce | Demontáž +montáž kazetového podh | 1368Des0000001543 | m3 | Deska | EXISTING | no | 2.054 | 1.325 | 2.054 | 0.103 | 5.75 | 0.103 | 1.55 | 0.05
 | Půdorys 1.PP | FLOOR | Demontáž +montáž podhledu FEAL | yes | Stávající FEAL podhled | Suché stavební práce | Demontáž +montáž podhledu FEAL | 1368Des0000000916 | m3 | Deska | EXISTING | no | 18.063 | 7.95 | 18.065 | 0.903 | 56.811 | 0.903 | 2.272 | 0.05
 | Půdorys 1.PP | FLOOR | Demontáž +montáž podhledu FEAL | yes | Stávající FEAL podhled | Suché stavební práce | Demontáž +montáž podhledu FEAL | 1368Des0000000884 | m3 | Deska | EXISTING | no | 21.967 | 2.294 | 21.969 | 1.098 | 54.628 | 1.098 | 9.575 | 0.05
 | Půdorys 1.PP | FLOOR | Demontáž +montáž kazetového podh | yes | Stávající kazetový podhled | Suché stavební práce | Demontáž +montáž kazetového podh | 1368Des0000000940 | m3 | Deska | EXISTING | no | 22.762 | 2.001 | 22.763 | 1.138 | 70.65 | 1.138 | 11.375 | 0.05
 | Půdorys 1.PP | FLOOR | SDK hladký bílý | yes | SDK | Suché stavební práce | SDK hladký bílý | 1368Des0000001629 | m3 | Deska | NEW | no | 2.048 | 0.45 | 2.048 | 0.102 | 10 | 0.102 | 4.55 | 0.05 | NEMSOK - Kód prvku: PH01.02.0001; Požární odolnost: bez požadavku; Výška svěšení: 0.45 m; Únosnost bodová: 0.5 kg
 | Půdorys 1.PP | FLOOR | Kazetový podhled bílý 0,6×0,6 | yes | RASTR 1 | Suché stavební práce | Kazetový podhled bílý 0,6×0,6 | 1368Des0000000028 | m3 | Deska | NEW | no | 21.392 | 1.725 | 21.392 | 1.07 | 30.95 | 1.07 | 12.4 | 0.05 | NEMSOK - Kód prvku: PH03.02.1003; Požární odolnost: bez požadavku; Výška svěšení: 0.5 m; Únosnost bodová: 0.5 kg
 | Půdorys 1.PP | FLOOR | Kazetový podhled bílý 0,6×0,6 | yes | RASTR 1 | Suché stavební práce | Kazetový podhled bílý 0,6×0,6 | 1368Des0000000025 | m3 | Deska | NEW | no | 16.75 | 3.35 | 16.75 | 0.837 | 16.7 | 0.837 | 5 | 0.05 | NEMSOK - Kód prvku: PH03.02.1002; Požární odolnost: bez požadavku; Výška svěšení: 0.2 m; Únosnost bodová: 0.5 kg
 | Půdorys 1.PP | FLOOR | Kazetový podhled bílý 0,6×0,6 | yes | RASTR 1 | Suché stavební práce | Kazetový podhled bílý 0,6×0,6 | 1368Des0000000606 | m3 | Deska | NEW | no | 41.014 | 2.385 | 41.014 | 2.051 | 39.8 | 2.051 | 17.2 | 0.05 | NEMSOK - Kód prvku: PH03.02.1007; Požární odolnost: bez požadavku; Únosnost bodová: 0.5 kg; Výška svěšení: 650.00
 | Půdorys 1.PP | FLOOR | Kazetový podhled bílý 0,6×0,6 | yes | RASTR 1 | Suché stavební práce | Kazetový podhled bílý 0,6×0,6 | 1368Des0000001368 | m3 | Deska | NEW | no | 11.726 | 2.802 | 11.726 | 0.586 | 14.12 | 0.586 | 4.185 | 0.05 | NEMSOK - Kód prvku: PH03.02.1012; Požární odolnost: bez požadavku; Únosnost bodová: 0.5 kg; Výška svěšení: 350.00 mm
 | Půdorys 1.PP | FLOOR | Kazetový podhled bílý 0,6×0,6 | yes | RASTR 1 | Suché stavební práce | Kazetový podhled bílý 0,6×0,6 | 1368Des0000001415 | m3 | Deska | NEW | no | 7.533 | 1.8 | 7.533 | 0.377 | 11.97 | 0.377 | 4.185 | 0.05 | NEMSOK - Kód prvku: PH03.02.1013; Požární odolnost: bez požadavku; Únosnost bodová: 0.5 kg; Výška svěšení: 350.00 mm
 | Půdorys 1.PP | FLOOR | Kazetový podhled bílý 0,6×0,6 | yes | RASTR 2 | Suché stavební práce | Kazetový podhled bílý 0,6×0,6 | 1368Des0000000100 | m3 | Deska | NEW | no | 1.845 | 2.15 | 1.845 | 0.092 | 6.1 | 0.092 | 0.858 | 0.05 | NEMSOK - Kód prvku: PH03.02.2002; Požární odolnost: bez požadavku; Únosnost bodová: 0.5 kg; Výška svěšení: 350.00 mm
 | Půdorys 1.PP | FLOOR | Kazetový podhled bílý 0,6×0,6 | yes | RASTR 2 | Suché stavební práce | Kazetový podhled bílý 0,6×0,6 | 1368Des0000000118 | m3 | Deska | NEW | no | 2.43 | 1.35 | 2.43 | 0.122 | 6.3 | 0.122 | 1.8 | 0.05 | NEMSOK - Kód prvku: PH03.02.2003; Požární odolnost: bez požadavku; Únosnost bodová: 0.5 kg; Výška svěšení: 350.00 mm
 | Půdorys 1.PP | FLOOR | Kazetový podhled bílý 0,6×0,6 | yes | RASTR 2 | Suché stavební práce | Kazetový podhled bílý 0,6×0,6 | 1368Des0000000121 | m3 | Deska | NEW | no | 4.07 | 1.536 | 4.07 | 0.203 | 8.7 | 0.203 | 2.65 | 0.05 | NEMSOK - Kód prvku: PH03.02.2004; Požární odolnost: bez požadavku; Únosnost bodová: 0.5 kg; Výška svěšení: 350.00 mm
 | Půdorys 1.PP | FLOOR | Kazetový podhled bílý 0,6×0,6 | yes | RASTR 2 | Suché stavební práce | Kazetový podhled bílý 0,6×0,6 | 1368Des0000000126 | m3 | Deska | NEW | no | 4.922 | 1.262 | 4.923 | 0.246 | 11.1 | 0.246 | 3.9 | 0.05 | NEMSOK - Kód prvku: PH03.02.2005; Požární odolnost: bez požadavku; Únosnost bodová: 0.5 kg; Výška svěšení: 350.00 mm
 | Půdorys 1.PP | FLOOR | Kazetový podhled bílý 0,6×0,6 | yes | RASTR 2 | Suché stavební práce | Kazetový podhled bílý 0,6×0,6 | 1368Des0000000202 | m3 | Deska | NEW | no | 1.93 | 1.55 | 1.93 | 0.096 | 5.59 | 0.096 | 1.245 | 0.05 | NEMSOK - Kód prvku: PH03.02.2007; Požární odolnost: bez požadavku; Únosnost bodová: 0.5 kg; Výška svěšení: 350.00 mm
 | Půdorys 1.PP | FLOOR | Kazetový podhled bílý 0,6×0,6 | yes | RASTR 2 | Suché stavební práce | Kazetový podhled bílý 0,6×0,6 | 1368Des0000000205 | m3 | Deska | NEW | no | 1.537 | 1.225 | 1.537 | 0.077 | 4.96 | 0.077 | 1.255 | 0.05 | NEMSOK - Kód prvku: PH03.02.2008; Požární odolnost: bez požadavku; Únosnost bodová: 0.5 kg; Výška svěšení: 350.00 mm
 | Půdorys 1.PP | FLOOR | Kazetový podhled bílý 0,6×0,6 | yes | RASTR 2 | Suché stavební práce | Kazetový podhled bílý 0,6×0,6 | 1368Des0000000232 | m3 | Deska | NEW | no | 1.61 | 1.15 | 1.61 | 0.08 | 5.1 | 0.08 | 1.4 | 0.05 | NEMSOK - Kód prvku: PH03.02.2009; Požární odolnost: bez požadavku; Únosnost bodová: 0.5 kg; Výška svěšení: 350.00 mm
 | Půdorys 1.PP | FLOOR | Kazetový podhled bílý 0,6×0,6 | yes | RASTR 2 | Suché stavební práce | Kazetový podhled bílý 0,6×0,6 | 1368Des0000000235 | m3 | Deska | NEW | no | 1.77 | 1.15 | 1.77 | 0.089 | 5.5 | 0.089 | 1.539 | 0.05 | NEMSOK - Kód prvku: PH03.02.2010; Požární odolnost: bez požadavku; Únosnost bodová: 0.5 kg; Výška svěšení: 350.00 mm
 | Půdorys 1.PP | FLOOR | Kazetový podhled bílý 0,6×0,6 | yes | RASTR 2 | Suché stavební práce | Kazetový podhled bílý 0,6×0,6 | 1368Des0000000646 | m3 | Deska | NEW | no | 3.026 | 1.15 | 3.026 | 0.151 | 7.14 | 0.151 | 2.631 | 0.05 | NEMSOK - Kód prvku: PH03.02.2011; Požární odolnost: bez požadavku; Únosnost bodová: 0.5 kg; Výška svěšení: 350.00 mm
 | Půdorys 1.PP | FLOOR | Kazetový podhled hyg. 0,6×0,6 | yes | RASTR 3 | Suché stavební práce | Kazetový podhled hyg. 0,6×0,6 | 1368Des0000000276 | m3 | Deska | NEW | no | 14.486 | 0.725 | 14.485 | 0.724 | 19.95 | 0.724 | 19.98 | 0.05 | NEMSOK - Kód prvku: PH03.02.3005; Požární odolnost: bez požadavku; Únosnost bodová: 0.5 kg; Výška svěšení: 350.00 mm
 | Půdorys 1.PP | FLOOR | Kazetový podhled hyg. 0,6×0,6 | yes | RASTR 3 | Suché stavební práce | Kazetový podhled hyg. 0,6×0,6 | 1368Des0000000304 | m3 | Deska | NEW | no | 18.42 | 5.45 | 18.421 | 0.921 | 19.3 | 0.921 | 3.38 | 0.05 | NEMSOK - Kód prvku: PH03.02.3009; Požární odolnost: bez požadavku; Únosnost bodová: 0.5 kg; Výška svěšení: 350.00 mm
 | Půdorys 1.PP | FLOOR | Kazetový podhled hyg. 0,6×0,6 | yes | RASTR 3 | Suché stavební práce | Kazetový podhled hyg. 0,6×0,6 | 1368Des0000001105 | m3 | Deska | NEW | no | 12.403 | 3.925 | 12.403 | 0.62 | 14.17 | 0.62 | 3.16 | 0.05 | NEMSOK - Kód prvku: PH03.02.3011; Požární odolnost: bez požadavku; Únosnost bodová: 0.5 kg; Výška svěšení: 350.00 mm
 | Půdorys 1.PP | FLOOR | Kazetový podhled hyg. 0,6×0,6 | yes | RASTR 3 | Suché stavební práce | Kazetový podhled hyg. 0,6×0,6 | 1368Des0000001132 | m3 | Deska | NEW | no | 12.64 | 4 | 12.64 | 0.632 | 14.32 | 0.632 | 3.16 | 0.05 | NEMSOK - Kód prvku: PH03.02.3012; Požární odolnost: bez požadavku; Únosnost bodová: 0.5 kg; Výška svěšení: 350.00 mm
 | Půdorys 1.PP | FLOOR | Kazetový podhled hyg. 0,6×0,6 | yes | RASTR 3 | Suché stavební práce | Kazetový podhled hyg. 0,6×0,6 | 1368Des0000001150 | m3 | Deska | NEW | no | 16.805 | 5.335 | 16.805 | 0.84 | 16.97 | 0.84 | 3.15 | 0.05 | NEMSOK - Kód prvku: PH03.02.3013; Požární odolnost: bez požadavku; Únosnost bodová: 0.5 kg; Výška svěšení: 350.00 mm
 | Půdorys 1.PP | FLOOR | Kazetový podhled hyg. 0,6×0,6 | yes | RASTR 3 | Suché stavební práce | Kazetový podhled hyg. 0,6×0,6 | 1368Des0000001240 | m3 | Deska | NEW | no | 12.235 | 2.975 | 12.235 | 0.612 | 14.37 | 0.612 | 4.112 | 0.05 | NEMSOK - Kód prvku: PH03.02.3016; Požární odolnost: bez požadavku; Únosnost bodová: 0.5 kg; Výška svěšení: 350.00 mm
 | Půdorys 1.PP | FLOOR | Kazetový podhled hyg. 0,6×0,6 | yes | RASTR 3 | Suché stavební práce | Kazetový podhled hyg. 0,6×0,6 | 1368Des0000001316 | m3 | Deska | NEW | no | 11.682 | 4.95 | 11.682 | 0.584 | 14.62 | 0.584 | 2.36 | 0.05 | NEMSOK - Kód prvku: PH03.02.3019; Požární odolnost: bez požadavku; Únosnost bodová: 0.5 kg; Výška svěšení: 350.00 mm
 | Půdorys 1.PP | FLOOR | Kazetový podhled bílý 0,6×0,6 | yes | RASTR 1 | Suché stavební práce | Kazetový podhled bílý 0,6×0,6 | 1368Des0000000491 | m3 | Deska | NEW | no | 33.258 | 0.675 | 33.258 | 1.663 | 37.4 | 1.663 | 49.272 | 0.05 | NEMSOK - Kód prvku: PH03.02.1006; Požární odolnost: bez požadavku; Únosnost bodová: 0.5 kg; Výška svěšení: 350.00 mm
 | Půdorys 1.PP | FLOOR | Kazetový podhled bílý 0,6×0,6 | yes | RASTR 2 | Suché stavební práce | Kazetový podhled bílý 0,6×0,6 | 1368Des0000000129 | m3 | Deska | NEW | no | 3.47 | 2.15 | 3.47 | 0.174 | 7.9 | 0.174 | 1.614 | 0.05 | NEMSOK - Kód prvku: PH03.02.2006; Požární odolnost: bez požadavku; Únosnost bodová: 0.5 kg; Výška svěšení: 250.00 mm
 | Půdorys 1.PP | FLOOR | Kazetový podhled hyg. 0,6×0,6 | yes | RASTR 3 | Suché stavební práce | Kazetový podhled hyg. 0,6×0,6 | 1368Des0000000264 | m3 | Deska | NEW | no | 3.398 | 0.971 | 3.398 | 0.17 | 9.2 | 0.17 | 3.5 | 0.05 | NEMSOK - Kód prvku: PH03.02.3001; Požární odolnost: bez požadavku; Únosnost bodová: 0.5 kg; Výška svěšení: 250.00 mm
 | Půdorys 1.PP | FLOOR | Kazetový podhled bílý 0,6×0,6 | yes | RASTR 1 | Suché stavební práce | Kazetový podhled bílý 0,6×0,6 | 1368Des0000000375 | m3 | Deska | NEW | no | 1.838 | 2.5 | 1.838 | 0.092 | 6.47 | 0.092 | 0.735 | 0.05 | NEMSOK - Kód prvku: PH03.02.1005; Požární odolnost: bez požadavku; Únosnost bodová: 0.5 kg; Výška svěšení: 250.00 mm
 | Půdorys 1.PP | FLOOR | Kazetový podhled bílý 0,6×0,6 | yes | RASTR 1 | Suché stavební práce | Kazetový podhled bílý 0,6×0,6 | 1368Des0000000716 | m3 | Deska | NEW | no | 1.323 | 0.735 | 1.323 | 0.066 | 5.07 | 0.066 | 1.8 | 0.05 | NEMSOK - Kód prvku: PH03.02.1008; Požární odolnost: bez požadavku; Únosnost bodová: 0.5 kg; Výška svěšení: 250.00 mm
 | Půdorys 1.PP | FLOOR | Kazetový podhled bílý 0,6×0,6 | yes | RASTR 1 | Suché stavební práce | Kazetový podhled bílý 0,6×0,6 | 1368Des0000001089 | m3 | Deska | NEW | no | 3.14 | 0.8 | 3.14 | 0.157 | 9.52 | 0.157 | 3.925 | 0.05 | NEMSOK - Kód prvku: PH03.02.1011; Požární odolnost: bez požadavku; Únosnost bodová: 0.5 kg; Výška svěšení: 250.00 mm
 | Půdorys 1.PP | FLOOR | Kazetový podhled hyg. 0,6×0,6 | yes | RASTR 3 | Suché stavební práce | Kazetový podhled hyg. 0,6×0,6 | 1368Des0000000267 | m3 | Deska | NEW | no | 3.398 | 0.971 | 3.399 | 0.17 | 9.2 | 0.17 | 3.5 | 0.05 | NEMSOK - Kód prvku: PH03.02.3002; Požární odolnost: bez požadavku; Únosnost bodová: 0.5 kg; Výška svěšení: 250.00 mm
 | Půdorys 1.PP | FLOOR | Kazetový podhled hyg. 0,6×0,6 | yes | RASTR 3 | Suché stavební práce | Kazetový podhled hyg. 0,6×0,6 | 1368Des0000000273 | m3 | Deska | NEW | no | 3.128 | 0.6 | 3.128 | 0.156 | 8.3 | 0.156 | 5.213 | 0.05 | NEMSOK - Kód prvku: PH03.02.3004; Požární odolnost: bez požadavku; Únosnost bodová: 0.5 kg; Výška svěšení: 250.00 mm
 | Půdorys 1.PP | FLOOR | Kazetový podhled hyg. 0,6×0,6 | yes | RASTR 3 | Suché stavební práce | Kazetový podhled hyg. 0,6×0,6 | 1368Des0000000279 | m3 | Deska | NEW | no | 3.78 | 1.2 | 3.78 | 0.189 | 8.7 | 0.189 | 3.15 | 0.05 | NEMSOK - Kód prvku: PH03.02.3006; Požární odolnost: bez požadavku; Únosnost bodová: 0.5 kg; Výška svěšení: 250.00 mm
 | Půdorys 1.PP | FLOOR | Kazetový podhled hyg. 0,6×0,6 | yes | RASTR 3 | Suché stavební práce | Kazetový podhled hyg. 0,6×0,6 | 1368Des0000000282 | m3 | Deska | NEW | no | 4.6 | 4 | 4.6 | 0.23 | 11.4 | 0.23 | 1.15 | 0.05 | NEMSOK - Kód prvku: PH03.02.3007; Požární odolnost: bez požadavku; Únosnost bodová: 0.5 kg; Výška svěšení: 250.00 mm
 | Půdorys 1.PP | FLOOR | Kazetový podhled hyg. 0,6×0,6 | yes | RASTR 3 | Suché stavební práce | Kazetový podhled hyg. 0,6×0,6 | 1368Des0000000285 | m3 | Deska | NEW | no | 4.71 | 3.925 | 4.71 | 0.236 | 10.25 | 0.236 | 1.2 | 0.05 | NEMSOK - Kód prvku: PH03.02.3008; Požární odolnost: bez požadavku; Únosnost bodová: 0.5 kg; Výška svěšení: 250.00 mm
 | Půdorys 1.PP | FLOOR | Kazetový podhled hyg. 0,6×0,6 | yes | RASTR 3 | Suché stavební práce | Kazetový podhled hyg. 0,6×0,6 | 1368Des0000000665 | m3 | Deska | NEW | no | 4.29 | 0.55 | 4.29 | 0.215 | 12.3 | 0.215 | 7.8 | 0.05 | NEMSOK - Kód prvku: PH03.02.3010; Požární odolnost: bez požadavku; Únosnost bodová: 0.5 kg; Výška svěšení: 250.00 mm
 | Půdorys 1.PP | FLOOR | Kazetový podhled hyg. 0,6×0,6 | yes | RASTR 3 | Suché stavební práce | Kazetový podhled hyg. 0,6×0,6 | 1368Des0000001187 | m3 | Deska | NEW | no | 2.139 | 2.725 | 2.139 | 0.107 | 7.02 | 0.107 | 0.785 | 0.05 | NEMSOK - Kód prvku: PH03.02.3014; Požární odolnost: bez požadavku; Únosnost bodová: 0.5 kg; Výška svěšení: 250.00 mm
 | Půdorys 1.PP | FLOOR | Kazetový podhled hyg. 0,6×0,6 | yes | RASTR 3 | Suché stavební práce | Kazetový podhled hyg. 0,6×0,6 | 1368Des0000001218 | m3 | Deska | NEW | no | 2.666 | 2.675 | 2.666 | 0.133 | 8.67 | 0.133 | 0.997 | 0.05 | NEMSOK - Kód prvku: PH03.02.3015; Požární odolnost: bez požadavku; Únosnost bodová: 0.5 kg; Výška svěšení: 250.00 mm
 | Půdorys 1.PP | FLOOR | Kazetový podhled bílý 0,6×0,6 | yes | RASTR 1 | Suché stavební práce | Kazetový podhled bílý 0,6×0,6 | 1368Des0000000365 | m3 | Deska | NEW | no | 76.24 | 2.35 | 76.24 | 3.812 | 69.6 | 3.812 | 32.443 | 0.05 | NEMSOK - Kód prvku: PH03.02.1004; Požární odolnost: bez požadavku; Únosnost bodová: 0.5 kg; Výška svěšení: 650.00
 | Půdorys 1.PP | FLOOR | Kazetový podhled bílý 0,6×0,6 | yes | RASTR 1 | Suché stavební práce | Kazetový podhled bílý 0,6×0,6 | 1368Des0000000728 | m3 | Deska | NEW | no | 5.7 | 4.75 | 5.7 | 0.285 | 11.9 | 0.285 | 1.2 | 0.05 | NEMSOK - Kód prvku: PH03.02.1009; Požární odolnost: bez požadavku; Únosnost bodová: 0.5 kg; Výška svěšení: 650.00
 | Půdorys 1.PP | FLOOR | Kazetový podhled bílý 0,6×0,6 | yes | RASTR 2 | Suché stavební práce | Kazetový podhled bílý 0,6×0,6 | 1368Des0000000008 | m3 | Deska | NEW | no | 1.485 | 1.65 | 1.485 | 0.074 | 5.1 | 0.074 | 0.9 | 0.05 | NEMSOK - Kód prvku: PH03.02.2001; Požární odolnost: bez požadavku; Únosnost bodová: 0.5 kg; Výška svěšení: 550.00
 | Půdorys 1.PP | FLOOR | Kazetový podhled bílý 0,6×0,6 | yes | RASTR 2 | Suché stavební práce | Kazetový podhled bílý 0,6×0,6 | 1368Des0000001049 | m3 | Deska | NEW | no | 1.111 | 1.235 | 1.112 | 0.056 | 4.27 | 0.056 | 0.9 | 0.05 | NEMSOK - Kód prvku: PH03.02.2012; Požární odolnost: bez požadavku; Únosnost bodová: 0.5 kg; Výška svěšení: 550.00
 | Půdorys 1.PP | FLOOR | Kazetový podhled hyg. 0,6×0,6 | yes | RASTR 3 | Suché stavební práce | Kazetový podhled hyg. 0,6×0,6 | 1368Des0000001268 | m3 | Deska | NEW | no | 12.366 | 2.45 | 12.366 | 0.618 | 14.52 | 0.618 | 5.047 | 0.05 | NEMSOK - Kód prvku: PH03.02.3017; Požární odolnost: bez požadavku; Únosnost bodová: 0.5 kg; Výška svěšení: 350.00 mm
 | Půdorys 1.PP | FLOOR | Kazetový podhled hyg. 0,6×0,6 | yes | RASTR 3 | Suché stavební práce | Kazetový podhled hyg. 0,6×0,6 | 1368Des0000001290 | m3 | Deska | NEW | no | 12.636 | 3.361 | 12.636 | 0.632 | 14.52 | 0.632 | 3.76 | 0.05 | NEMSOK - Kód prvku: PH03.02.3018; Požární odolnost: bez požadavku; Únosnost bodová: 0.5 kg; Výška svěšení: 350.00 mm
 | Půdorys 1.PP | FLOOR | Kazetový podhled hyg. 0,6×0,6 | yes | RASTR 3 | Suché stavební práce | Kazetový podhled hyg. 0,6×0,6 | 1368Des0000000270 | m3 | Deska | NEW | no | 7.92 | 4.95 | 7.92 | 0.396 | 13.1 | 0.396 | 1.6 | 0.05 | NEMSOK - Kód prvku: PH03.02.3003; Požární odolnost: bez požadavku; Únosnost bodová: 0.5 kg; Výška svěšení: 550.00
 | Půdorys 1.PP | FLOOR | Kazetový podhled bílý 0,6×0,6 | yes | RASTR 1 | Suché stavební práce | Kazetový podhled bílý 0,6×0,6 | 1368Des0000000972 | m3 | Deska | NEW | no | 0.492 | 1.2 | 0.492 | 0.025 | 3.22 | 0.025 | 0.41 | 0.05 | NEMSOK - Kód prvku: PH03.02.1010; Požární odolnost: bez požadavku; Výška svěšení: 0.5 m; Únosnost bodová: 0.5 kg
 | Půdorys 1.PP | FLOOR | Kazetový podhled bílý 0,6×0,6 | yes | RASTR 1 | Suché stavební práce | Kazetový podhled bílý 0,6×0,6 | 1368Des0000000022 | m3 | Deska | NEW | no | 27.94 | 4.4 | 27.94 | 1.397 | 21.5 | 1.397 | 6.35 | 0.05 | NEMSOK - Kód prvku: PH03.02.1001; Požární odolnost: bez požadavku; Výška svěšení: 0.2 m; Únosnost bodová: 0.5 kg
Podkladní beton | Půdorys 1.PP | FLOOR | BETONOVÁ KCE | yes | Betonová deska (Atribut objektu!) | Betonářské práce | BETONOVÁ KCE | 1380Des0000000010 | m3 | Deska | NEW | no | 49.964 | 1.65 | 49.965 | 2.498 | 129.18 | 2.498 | 30.282 | 0.05 | NEMSOK - Kód prvku: DZ01.02.0007; Stupeň vyztužení: 0; Třída pevnosti betonu: C12/15-X0; Označení: Podkladní beton
Podkladní beton | Půdorys 1.PP | FLOOR | BETONOVÁ KCE | yes | Betonová deska (Atribut objektu!) | Betonářské práce | BETONOVÁ KCE | 1380Des0000000035 | m3 | Deska | NEW | no | 40.681 | 2.776 | 40.683 | 2.034 | 107.955 | 2.034 | 14.655 | 0.05 | NEMSOK - Kód prvku: DZ01.02.0004; Stupeň vyztužení: 0; Třída pevnosti betonu: C12/15-X0; Označení: Podkladní beton
Podkladní beton | Půdorys 1.PP | FLOOR | BETONOVÁ KCE | yes | Betonová deska (Atribut objektu!) | Betonářské práce | BETONOVÁ KCE | 1380Des0000000078 | m3 | Deska | NEW | no | 184.982 | 4.274 | 184.983 | 18.498 | 91.33 | 18.498 | 43.282 | 0.1 | NEMSOK - Kód prvku: DZ01.02.0006; Stupeň vyztužení: 0; Třída pevnosti betonu: C12/15-X0; Označení: Podkladní beton
Podkladní beton | Půdorys 1.PP | FLOOR | BETONOVÁ KCE | yes | Betonová deska (Atribut objektu!) | Betonářské práce | BETONOVÁ KCE | 1380Des0000000111 | m3 | Deska | NEW | no | 114.602 | 8.183 | 114.603 | 11.46 | 66.58 | 11.46 | 14.005 | 0.1 | NEMSOK - Kód prvku: DZ01.02.0005; Stupeň vyztužení: 0; Třída pevnosti betonu: C12/15-X0; Označení: Podkladní beton
Podkladní beton | Půdorys 1.PP | FLOOR | BETONOVÁ KCE | yes | Betonová deska (Atribut objektu!) | Betonářské práce | BETONOVÁ KCE | 1380Des0000000148 | m3 | Deska | NEW | no | 3.949 | 2.2 | 3.949 | 0.395 | 7.99 | 0.395 | 1.795 | 0.1 | NEMSOK - Kód prvku: DZ01.02.0001; Stupeň vyztužení: 0; Třída pevnosti betonu: C12/15-X0; Označení: Podkladní beton
Podkladní beton | Půdorys 1.PP | FLOOR | BETONOVÁ KCE | yes | Betonová deska (Atribut objektu!) | Betonářské práce | BETONOVÁ KCE | 1380Des0000000157 | m3 | Deska | NEW | no | 42.279 | 2.627 | 42.28 | 2.114 | 113.564 | 2.114 | 16.095 | 0.05 | NEMSOK - Kód prvku: DZ01.02.0008; Stupeň vyztužení: 0; Třída pevnosti betonu: C12/15-X0; Označení: Podkladní beton
Podkladní beton | Půdorys 1.PP | FLOOR | BETONOVÁ KCE | yes | Betonová deska (Atribut objektu!) | Betonářské práce | BETONOVÁ KCE | 1380Des0000000204 | m3 | Deska | NEW | no | 3.619 | 2.2 | 3.949 | 0.362 | 7.69 | 0.362 | 1.645 | 0.1 | NEMSOK - Kód prvku: DZ01.02.0001; Stupeň vyztužení: 0; Třída pevnosti betonu: C12/15-X0; Označení: Podkladní beton
Podkladní beton | Půdorys 1.PP | FLOOR | BETONOVÁ KCE | yes | Betonová deska (Atribut objektu!) | Betonářské práce | BETONOVÁ KCE | 1380Des0000000205 | m3 | Deska | NEW | no | 40.681 | 2.776 | 40.683 | 2.034 | 107.955 | 2.034 | 14.655 | 0.05 | NEMSOK - Kód prvku: DZ01.02.0004; Stupeň vyztužení: 0; Třída pevnosti betonu: C12/15-X0; Označení: Podkladní beton
Podkladní beton | Půdorys 1.PP | FLOOR | BETONOVÁ KCE | yes | Betonová deska (Atribut objektu!) | Betonářské práce | BETONOVÁ KCE | 1380Des0000000206 | m3 | Deska | NEW | no | 114.602 | 8.183 | 114.603 | 11.46 | 66.58 | 11.46 | 14.005 | 0.1 | NEMSOK - Kód prvku: DZ01.02.0005; Stupeň vyztužení: 0; Třída pevnosti betonu: C12/15-X0; Označení: Podkladní beton
Podkladní beton | Půdorys 1.PP | FLOOR | BETONOVÁ KCE | yes | Betonová deska (Atribut objektu!) | Betonářské práce | BETONOVÁ KCE | 1380Des0000000207 | m3 | Deska | NEW | no | 3.135 | 1.65 | 3.135 | 0.157 | 7.1 | 0.157 | 1.9 | 0.05 | NEMSOK - Kód prvku: DZ01.02.0002; Stupeň vyztužení: 0; Třída pevnosti betonu: C12/15-X0; Označení: Podkladní beton
Podkladní beton | Půdorys 1.PP | FLOOR | BETONOVÁ KCE | yes | Betonová deska (Atribut objektu!) | Betonářské práce | BETONOVÁ KCE | 1380Des0000000219 | m3 | Deska | NEW | no | 2.09 | 1.9 | 2.09 | 0.105 | 6 | 0.105 | 1.1 | 0.05 | NEMSOK - Kód prvku: DZ01.02.0001; Stupeň vyztužení: 0; Třída pevnosti betonu: C12/15-X0; Označení: Podkladní beton
 | Půdorys 1.NP | FLOOR | ROŠT | yes | Rošt (Atribut objektu!) | Zámečnické práce | ROŠT | 1452Des1096132955 | m2 | Deska | EXISTING |  | 3.094 | 2.8 | 3.094 | 0.093 | 7.81 | 0.093 | 1.105 | 0.03
 | Půdorys 1.NP | FLOOR | ROŠT | yes | Rošt (Atribut objektu!) | Zámečnické práce | ROŠT | 1452Des1096133048 | m2 | Deska | EXISTING |  | 4.254 | 3.85 | 4.254 | 0.128 | 9.91 | 0.128 | 1.105 | 0.03
 | Půdorys 1.NP | FLOOR | ROŠT | yes | Rošt (Atribut objektu!) | Zámečnické práce | ROŠT | 1452Des1096133036 | m2 | Deska | EXISTING |  | 2.536 | 2.295 | 2.536 | 0.076 | 6.8 | 0.076 | 1.105 | 0.03
 | Půdorys 1.NP | FLOOR | ROŠT | yes | Rošt (Atribut objektu!) | Zámečnické práce | ROŠT | 1452Des1096133028 | m2 | Deska | EXISTING |  | 3.094 | 2.8 | 3.094 | 0.093 | 7.81 | 0.093 | 1.105 | 0.03
 | Půdorys 1.NP | FLOOR | ROŠT | yes | Rošt (Atribut objektu!) | Zámečnické práce | ROŠT | 1452Des1096133001 | m2 | Deska | EXISTING |  | 3.094 | 2.8 | 3.094 | 0.093 | 7.81 | 0.093 | 1.105 | 0.03
 | Půdorys 1.NP | FLOOR | ROŠT | yes | Rošt (Atribut objektu!) | Zámečnické práce | ROŠT | 1452Des1096132993 | m2 | Deska | EXISTING |  | 3.094 | 2.8 | 3.094 | 0.093 | 7.81 | 0.093 | 1.105 | 0.03
 | Půdorys 1.NP | FLOOR | ROŠT | yes | Rošt (Atribut objektu!) | Zámečnické práce | ROŠT | 1452Des1096133020 | m2 | Deska | EXISTING |  | 3.094 | 2.8 | 3.084 | 0.093 | 7.81 | 0.093 | 1.105 | 0.03
 | Půdorys 1.NP | FLOOR | RZT | yes | Betonová deska (Atribut objektu!) | Betonářské práce | RZT | 1454Des0000000826 | m3 | Deska | EXISTING | yes | 8.26 | 5.9 | 8.26 | 2.065 | 14.6 | 2.065 | 1.4 | 0.25
 | Půdorys 1.NP | FLOOR | PZD | yes | Betonová deska (Atribut objektu!) | Betonářské práce | PZD | 1454Des0000000824 | m3 | Deska | EXISTING | yes | 12.98 | 5.9 | 12.98 | 3.245 | 16.2 | 3.245 | 2.2 | 0.25
 | Půdorys 1.NP | FLOOR | DZH | yes | Betonová deska (Atribut objektu!) | Betonářské práce | DZH | 1454Des0000000828 | m3 | Deska | EXISTING | yes | 5.44 | 3.4 | 5.44 | 1.36 | 10 | 1.36 | 1.6 | 0.25
 | Půdorys 1.NP | FLOOR | RZT | yes | Betonová deska (Atribut objektu!) | Betonářské práce | RZT | 1454Des0000000864 | m3 | Deska | EXISTING | yes | 8.4 | 6 | 8.4 | 2.1 | 14.8 | 2.1 | 1.4 | 0.25
 | Půdorys 1.NP | FLOOR | RZT | yes | Betonová deska (Atribut objektu!) | Betonářské práce | RZT | 1454Des0000000866 | m3 | Deska | EXISTING | yes | 8.4 | 6 | 8.4 | 2.1 | 14.8 | 2.1 | 1.4 | 0.25
 | Půdorys 1.NP | FLOOR | PZD | yes | Betonová deska (Atribut objektu!) | Betonářské práce | PZD | 1454Des0000000903 | m3 | Deska | EXISTING | yes | 31.746 | 2.2 | 31.646 | 7.937 | 33.26 | 7.912 | 14.43 | 0.25
 | Půdorys 1.NP | FLOOR | VĚNEC | yes | Betonová deska (Atribut objektu!) | Betonářské práce | VĚNEC | 1454Des0000001012 | m3 | Deska | EXISTING | yes | 7.597 | 1.07 | 7.597 | 1.899 | 16.34 | 1.899 | 7.1 | 0.25
 | Půdorys 1.NP | FLOOR | RZT | yes | Betonová deska (Atribut objektu!) | Betonářské práce | RZT | 1454Des0000000860 | m3 | Deska | EXISTING | yes | 16.8 | 12 | 16.8 | 4.2 | 26.8 | 4.2 | 1.4 | 0.25
 | Půdorys 1.NP | FLOOR | PZD | yes | Betonová deska (Atribut objektu!) | Betonářské práce | PZD | 1454Des0000000928 | m3 | Deska | EXISTING | yes | 99.12 | 25.2 | 97.895 | 24.78 | 86.4 | 24.474 | 3.933 | 0.25
 | Půdorys 1.NP | FLOOR | PZD | yes | Betonová deska (Atribut objektu!) | Betonářské práce | PZD | 1454Des0000000874 | m3 | Deska | EXISTING | yes | 62.66 | 2.8 | 61.85 | 15.665 | 43.5 | 15.463 | 22.379 | 0.25
 | Půdorys 1.NP | FLOOR | PZD | yes | Betonová deska (Atribut objektu!) | Betonářské práce | PZD | 1454Des0000000830 | m3 | Deska | EXISTING | yes | 9.345 | 2.67 | 9.345 | 2.336 | 12.34 | 2.336 | 3.5 | 0.25
 | Půdorys 1.NP | FLOOR | RZT | yes | Betonová deska (Atribut objektu!) | Betonářské práce | RZT | 1454Des0000000862 | m3 | Deska | EXISTING | yes | 20.202 | 14.43 | 20.202 | 5.051 | 31.66 | 5.051 | 1.4 | 0.25
 | Půdorys 1.NP | FLOOR | PZD | yes | Betonová deska (Atribut objektu!) | Betonářské práce | PZD | 1454Des0000000330 | m3 | Deska | EXISTING | yes | 21.195 | 2.7 | 21.126 | 2.12 | 21.1 | 2.113 | 7.85 | 0.1
 | Půdorys 1.NP | FLOOR | PZD | yes | Betonová deska (Atribut objektu!) | Betonářské práce | PZD | 1454Des0000000059 | m3 | Deska | EXISTING | yes | 6.93 | 3.3 | 6.65 | 0.693 | 10.8 | 0.665 | 2.1 | 0.1
 | Půdorys 1.NP | FLOOR | PZD | yes | Betonová deska (Atribut objektu!) | Betonářské práce | PZD | 1454Des0000000063 | m3 | Deska | EXISTING | yes | 8.75 | 3.5 | 8.75 | 2.187 | 12 | 2.037 | 2.5 | 0.25
 | Půdorys 1.NP | FLOOR | RZT | yes | Betonová deska (Atribut objektu!) | Betonářské práce | RZT | 1454Des0000000351 | m3 | Deska | EXISTING | yes | 20.16 | 14.4 | 20.16 | 5.04 | 31.6 | 5.04 | 1.4 | 0.25
 | Půdorys 1.NP | FLOOR | RZT | yes | Betonová deska (Atribut objektu!) | Betonářské práce | RZT | 1454Des0000000348 | m3 | Deska | EXISTING | yes | 20.16 | 14.4 | 20.16 | 5.04 | 31.6 | 5.04 | 1.4 | 0.25
 | Půdorys 1.NP | FLOOR | PZD | yes | Betonová deska (Atribut objektu!) | Betonářské práce | PZD | 1454Des0000000355 | m3 | Deska | EXISTING | yes | 66.24 | 4.6 | 65.555 | 16.56 | 38 | 16.389 | 14.4 | 0.25
 | Půdorys 1.NP | FLOOR | RZT | yes | Betonová deska (Atribut objektu!) | Betonářské práce | RZT | 1454Des0000000886 | m3 | Deska | EXISTING | yes | 8.68 | 6.2 | 8.68 | 2.17 | 15.2 | 2.17 | 1.4 | 0.25
 | Půdorys 1.NP | FLOOR | RZT | yes | Betonová deska (Atribut objektu!) | Betonářské práce | RZT | 1454Des0000000888 | m3 | Deska | EXISTING | yes | 3.64 | 2.6 | 3.64 | 0.91 | 8 | 0.91 | 1.4 | 0.25
 | Půdorys 1.NP | FLOOR | PZD | yes | Betonová deska (Atribut objektu!) | Betonářské práce | PZD | 1454Des0000000897 | m3 | Deska | EXISTING | yes | 103.6 | 25.2 | 99.772 | 25.9 | 82.8 | 24.943 | 4.111 | 0.25
 | Půdorys 1.NP | FLOOR | PZD | yes | Betonová deska (Atribut objektu!) | Betonářské práce | PZD | 1454Des0000000914 | m3 | Deska | EXISTING | yes | 55.44 | 25.2 | 54.87 | 13.86 | 54.8 | 13.717 | 2.2 | 0.25
 | Půdorys 1.NP | FLOOR | PZD | yes | Betonová deska (Atribut objektu!) | Betonářské práce | PZD | 1454Des0000000402 | m3 | Deska | EXISTING | yes | 66.24 | 4.6 | 65.751 | 16.56 | 38 | 16.438 | 14.4 | 0.25
 | Půdorys 1.NP | FLOOR | PZD | yes | Betonová deska (Atribut objektu!) | Betonářské práce | PZD | 1454Des0000000395 | m3 | Deska | EXISTING | yes | 66.24 | 4.6 | 65.08 | 16.56 | 38 | 16.27 | 14.4 | 0.25
 | Půdorys 1.NP | FLOOR | PZD | yes | Betonová deska (Atribut objektu!) | Betonářské práce | PZD | 1454Des0000000388 | m3 | Deska | EXISTING | yes | 66.24 | 4.6 | 65.686 | 16.56 | 38 | 16.422 | 14.4 | 0.25
 | Půdorys 1.NP | FLOOR | RZT | yes | Betonová deska (Atribut objektu!) | Betonářské práce | RZT | 1454Des0000000352 | m3 | Deska | EXISTING | yes | 20.16 | 14.4 | 20.142 | 5.04 | 31.6 | 5.036 | 1.4 | 0.25
 | Půdorys 1.NP | FLOOR | RZT | yes | Betonová deska (Atribut objektu!) | Betonářské práce | RZT | 1454Des0000000353 | m3 | Deska | EXISTING | yes | 20.16 | 1.4 | 20.142 | 5.04 | 31.6 | 5.036 | 14.4 | 0.25
 | Půdorys 1.NP | FLOOR | RZT | yes | Betonová deska (Atribut objektu!) | Betonářské práce | RZT | 1454Des0000000354 | m3 | Deska | EXISTING | yes | 20.16 | 14.4 | 20.142 | 5.04 | 31.6 | 5.036 | 1.4 | 0.25
 | Půdorys 1.NP | FLOOR | RZT | yes | Betonová deska (Atribut objektu!) | Betonářské práce | RZT | 1454Des0000000868 | m3 | Deska | EXISTING | yes | 35.28 | 25.2 | 35.164 | 8.82 | 53.2 | 8.791 | 1.4 | 0.25
 | Půdorys 1.NP | FLOOR | PZD | yes | Betonová deska (Atribut objektu!) | Betonářské práce | PZD | 1454Des0000000855 | m3 | Deska | EXISTING | yes | 99.12 | 25.2 | 97.728 | 24.78 | 89.2 | 24.432 | 3.933 | 0.25
 | Půdorys 1.NP | FLOOR | PZD | yes | Betonová deska (Atribut objektu!) | Betonářské práce | PZD | 1454Des0000000838 | m3 | Deska | EXISTING | yes | 55.44 | 2.2 | 54.749 | 13.86 | 54.8 | 13.687 | 25.2 | 0.25
 | Půdorys 1.NP | FLOOR | RZT | yes | Betonová deska (Atribut objektu!) | Betonářské práce | RZT | 1454Des0000000872 | m3 | Deska | EXISTING | yes | 35.28 | 25.2 | 35.231 | 8.82 | 53.2 | 8.808 | 1.4 | 0.25
 | Půdorys 1.NP | FLOOR | RZT | yes | Betonová deska (Atribut objektu!) | Betonářské práce | RZT | 1454Des0000000870 | m3 | Deska | EXISTING | yes | 37.1 | 26.5 | 37.051 | 9.275 | 55.8 | 9.263 | 1.4 | 0.25
 | Půdorys 1.NP | FLOOR | RZT | yes | Betonová deska (Atribut objektu!) | Betonářské práce | RZT | 1454Des0000000908 | m3 | Deska | EXISTING | yes | 37.1 | 26.5 | 37.051 | 9.275 | 55.8 | 9.263 | 1.4 | 0.25
 | Půdorys 1.NP | FLOOR | PZD | yes | Betonová deska (Atribut objektu!) | Betonářské práce | PZD | 1454Des0000001258 | m3 | Deska | EXISTING | yes | 2.64 | 2.2 | 2.486 | 0.66 | 6.8 | 0.621 | 1.2 | 0.25
 | Půdorys 1.NP | FLOOR | PZD | yes | Betonová deska (Atribut objektu!) | Betonářské práce | PZD | 1454Des0000001251 | m3 | Deska | EXISTING | yes | 5.52 | 4.6 | 5.198 | 1.38 | 11.6 | 1.299 | 1.2 | 0.25
 | Půdorys 1.NP | FLOOR | PZD | yes | Betonová deska (Atribut objektu!) | Betonářské práce | PZD | 1454Des0000001244 | m3 | Deska | EXISTING | yes | 5.52 | 4.6 | 5.198 | 1.38 | 11.6 | 1.3 | 1.2 | 0.25
 | Půdorys 1.NP | FLOOR | RZT | yes | Betonová deska (Atribut objektu!) | Betonářské práce | RZT | 1454Des0000000923 | m3 | Deska | EXISTING | yes | 37.1 | 26.5 | 37.002 | 9.275 | 55.8 | 9.251 | 1.4 | 0.25
 | Půdorys 1.NP | FLOOR | RZT | yes | Betonová deska (Atribut objektu!) | Betonářské práce | RZT | 1454Des0000000916 | m3 | Deska | EXISTING | yes | 37.1 | 26.5 | 36.984 | 9.275 | 55.8 | 9.246 | 1.4 | 0.25
 | Půdorys 1.NP | FLOOR | PZD | yes | Betonová deska (Atribut objektu!) | Betonářské práce | PZD | 1454Des0000001681 | m3 | Deska | EXISTING | yes | 81.35 | 6.723 | 81.297 | 16.27 | 39.3 | 16.259 | 12.1 | 0.2
 | Půdorys 1.NP | FLOOR | Kuchyňská deska | yes | Kuchyňská deska | Truhlářské práce | Kuchyňská deska | 1464Des1096177506 | m2 | Deska | NEW |  | 0.749 | 1.8 | 0.752 | 0.022 | 7.81 | 0.022 | 0.416 | 0.03 | NEMSOK - Kód prvku: TV00.03.0001; Číslo místnosti: 1.02; Podlaží: 1.NP
 | Půdorys 1.NP | FLOOR | Kuchyňská deska | yes | Kuchyňská deska | Truhlářské práce | Kuchyňská deska | 1464Des1096177521 | m2 | Deska | NEW |  | 1.275 | 2.4 | 1.276 | 0.038 | 7.568 | 0.038 | 0.531 | 0.03 | NEMSOK - Kód prvku: TV00.03.0004; Číslo místnosti: 1.05; Podlaží: 1.NP
 | Půdorys 1.NP | FLOOR | Pracovní deska | yes | Pracovní deska | Truhlářské práce | Pracovní deska | 1464Des1096177556 | m2 | Deska | NEW |  | 1.289 | 2.7 | 1.292 | 0.039 | 9.61 | 0.039 | 0.477 | 0.03 | NEMSOK - Kód prvku: TV00.03.0005; Číslo místnosti: 1.08; Podlaží: 1.NP
 | Půdorys 1.NP | FLOOR | Kuchyňská deska | yes | Kuchyňská deska | Truhlářské práce | Kuchyňská deska | 1464Des1096159653 | m2 | Deska | NEW | no | 1.452 | 2.4 | 1.455 | 0.044 | 10.714 | 0.044 | 0.605 | 0.03 | NEMSOK - Kód prvku: TV00.03.0007; Číslo místnosti: 1.18; Podlaží: 1.NP
 | Půdorys 1.NP | FLOOR | Kuchyňská deska | yes | Kuchyňská deska | Truhlářské práce | Kuchyňská deska | 1464Des1096221349 | m2 | Deska | NEW | no | 2.732 | 0.6 | 2.734 | 0.082 | 17.759 | 0.082 | 4.553 | 0.03 | NEMSOK - Kód prvku: TV00.03.2002; Číslo místnosti: K1.08; Podlaží: 1.NP
 | Půdorys 1.NP | FLOOR | Kuchyňská deska | yes | Kuchyňská deska | Truhlářské práce | Kuchyňská deska | 1464Des1096141414 | m2 | Deska | NEW | no | 1.102 | 1.836 | 1.102 | 0.033 | 4.872 | 0.033 | 0.6 | 0.03 | NEMSOK - Kód prvku: TV00.03.2002; Číslo místnosti: K1.08; Podlaží: 1.NP
 | Půdorys 1.NP | FLOOR | Kuchyňská deska | yes | Kuchyňská deska | Truhlářské práce | Kuchyňská deska | 1464Des1096122528 | m2 | Deska | NEW | no | 2.243 | 4.1 | 2.243 | 0.067 | 11.194 | 0.067 | 0.547 | 0.03 | NEMSOK - Kód prvku: TV00.03.2001; Číslo místnosti: K1.09; Podlaží: 1.NP
 | Půdorys 1.NP | FLOOR | Kuchyňská deska | yes | Kuchyňská deska | Truhlářské práce | Kuchyňská deska | 1464Des1096124890 | m2 | Deska | NEW | no | 0.863 | 0.6 | 0.617 | 0.026 | 6.594 | 0.026 | 1.438 | 0.03 | NEMSOK - Kód prvku: TV00.03.2001; Číslo místnosti: K1.09; Podlaží: 1.NP
 | Půdorys 1.NP | FLOOR | Kuchyňská deska | yes | Kuchyňská deska | Truhlářské práce | Kuchyňská deska | 1464Des1096124793 | m2 | Deska | NEW | no | 0.773 | 0.6 | 0.773 | 0.023 | 6.294 | 0.023 | 1.288 | 0.03 | NEMSOK - Kód prvku: TV00.03.2001; Číslo místnosti: K1.09; Podlaží: 1.NP
 | Půdorys 1.NP | FLOOR | Kuchyňská deska | yes | Kuchyňská deska | Truhlářské práce | Kuchyňská deska | 1464Des1096124947 | m2 | Deska | NEW | no | 0.956 | 1.85 | 0.956 | 0.029 | 6.439 | 0.029 | 0.517 | 0.03 | NEMSOK - Kód prvku: TV00.03.2001; Číslo místnosti: K1.09; Podlaží: 1.NP
 | Půdorys 1.NP | FLOOR | Nerezová deska | yes | 0 | Truhlářské práce | Nerezová deska | 1464Des1096175804 | m2 | Pracovní linka | NEW | no | 0.794 | 0.465 | 0.794 | 0.024 | 8.21 | 0.024 | 1.709 | 0.03 | NEMSOK - Kód prvku: SB.17.; Číslo místnosti: 1.06; Podlaží: 1.NP
 | Půdorys 1.NP | FLOOR | Nerezová deska | yes | 0 | Truhlářské práce | Nerezová deska | 1464Des1096175021 | m2 | Pracovní linka | NEW | no | 2.073 | 0.488 | 2.047 | 0.062 | 13.162 | 0.061 | 4.25 | 0.03 | NEMSOK - Kód prvku: SB.18.; Číslo místnosti: 1.29; Podlaží: 1.NP
 | Půdorys 1.NP | FLOOR | KRYCÍ ROŠT ANGLICKÉHO DVORKU | yes | Rošt (Atribut objektu!) | Zámečnické práce | KRYCÍ ROŠT ANGLICKÉHO DVORKU | 1464Des1096155908 | Kus | I.Z4.1 | NEW |  | 3.094 | 2.8 | 3.094 | 0.093 | 7.81 | 0.093 | 1.105 | 0.03 | NEMSOK - Kód prvku: ZV00.03.4001; Číslo místnosti: exteriér; Podlaží: 1.NP; Požární odolnost: bez požadavku; Hmotnost (2): 60 kg
 | Půdorys 1.NP | FLOOR | KRYCÍ ROŠT ANGLICKÉHO DVORKU | yes | Rošt (Atribut objektu!) | Zámečnické práce | KRYCÍ ROŠT ANGLICKÉHO DVORKU | 1464Des1096155910 | Kus | I.Z4.1 | NEW |  | 3.094 | 2.8 | 3.094 | 0.093 | 7.81 | 0.093 | 1.105 | 0.03 | NEMSOK - Kód prvku: ZV00.03.4001; Číslo místnosti: exteriér; Podlaží: 1.NP; Požární odolnost: bez požadavku; Hmotnost (2): 60 kg
 | Půdorys 1.NP | FLOOR | KRYCÍ ROŠT ANGLICKÉHO DVORKU | yes | Rošt (Atribut objektu!) | Zámečnické práce | KRYCÍ ROŠT ANGLICKÉHO DVORKU | 1464Des1096155912 | Kus | I.Z4.1 | NEW |  | 3.094 | 2.8 | 3.094 | 0.093 | 7.81 | 0.093 | 1.105 | 0.03 | NEMSOK - Kód prvku: ZV00.03.4001; Číslo místnosti: exteriér; Podlaží: 1.NP; Požární odolnost: bez požadavku; Hmotnost (2): 60 kg
 | Půdorys 1.NP | FLOOR | KRYCÍ ROŠT ANGLICKÉHO DVORKU | yes | Rošt (Atribut objektu!) | Zámečnické práce | KRYCÍ ROŠT ANGLICKÉHO DVORKU | 1464Des1096155915 | Kus | I.Z4.2 | NEW |  | 3.564 | 3.225 | 3.564 | 0.107 | 8.66 | 0.107 | 1.105 | 0.03 | NEMSOK - Kód prvku: ZV00.03.4002; Číslo místnosti: exteriér; Podlaží: 1.NP; Požární odolnost: bez požadavku; Hmotnost (2): 70 kg
 | Půdorys 1.NP | FLOOR | KRYCÍ ROŠT ANGLICKÉHO DVORKU | yes | Rošt (Atribut objektu!) | Zámečnické práce | KRYCÍ ROŠT ANGLICKÉHO DVORKU | 1464Des1096155958 | m2 | Deska | NEW | no | 1.751 | 2.11 | 1.751 | 0.053 | 5.88 | 0.053 | 0.83 | 0.03 | NEMSOK - Kód prvku: OV00.02.0001; Podlaží: 1.NP
 | Půdorys 1.NP | FLOOR | KRYCÍ ROŠT ANGLICKÉHO DVORKU | yes | Rošt (Atribut objektu!) | Zámečnické práce | KRYCÍ ROŠT ANGLICKÉHO DVORKU | 1464Des1096169021 | m2 | Deska | NEW |  | 1.349 | 1.31 | 1.349 | 0.04 | 4.68 | 0.04 | 1.03 | 0.03 | NEMSOK - Kód prvku: OV00.02.0001; Podlaží: 1.NP
 | Půdorys 1.NP | FLOOR | KRYCÍ ROŠT ANGLICKÉHO DVORKU | yes | Rošt (Atribut objektu!) | Zámečnické práce | KRYCÍ ROŠT ANGLICKÉHO DVORKU | 1464Des1096155945 | m2 | Deska | NEW |  | 1.349 | 1.31 | 1.349 | 0.04 | 4.68 | 0.04 | 1.03 | 0.03 | NEMSOK - Kód prvku: OV00.02.0001; Podlaží: 1.NP
 | Půdorys 1.NP | FLOOR | KRYCÍ ROŠT ANGLICKÉHO DVORKU | yes | Rošt (Atribut objektu!) | Zámečnické práce | KRYCÍ ROŠT ANGLICKÉHO DVORKU | 1464Des1096155960 | m2 | Deska | NEW | no | 1.751 | 2.11 | 1.751 | 0.053 | 5.88 | 0.053 | 0.83 | 0.03 | NEMSOK - Kód prvku: OV00.02.0001; Podlaží: 1.NP
 | Půdorys 1.NP | FLOOR | KRYCÍ ROŠT ANGLICKÉHO DVORKU | yes | Rošt (Atribut objektu!) | Zámečnické práce | KRYCÍ ROŠT ANGLICKÉHO DVORKU | 1464Des1096155959 | m2 | Deska | NEW | no | 1.751 | 2.11 | 1.751 | 0.053 | 5.88 | 0.053 | 0.83 | 0.03 | NEMSOK - Kód prvku: OV00.02.0001; Podlaží: 1.NP
 | Půdorys 1.NP | FLOOR | KRYCÍ ROŠT ANGLICKÉHO DVORKU | yes | Rošt (Atribut objektu!) | Zámečnické práce | KRYCÍ ROŠT ANGLICKÉHO DVORKU | 1464Des1096156049 | m2 | Deska | NEW | no | 2.173 | 2.11 | 2.173 | 0.065 | 6.28 | 0.065 | 1.03 | 0.03 | NEMSOK - Kód prvku: OV00.02.0001; Podlaží: 1.NP
 | Půdorys 1.NP | FLOOR | KRYCÍ ROŠT ANGLICKÉHO DVORKU | yes | Rošt (Atribut objektu!) | Zámečnické práce | KRYCÍ ROŠT ANGLICKÉHO DVORKU | 1464Des1096156054 | m2 | Deska | NEW | no | 2.173 | 2.11 | 2.173 | 0.065 | 6.28 | 0.065 | 1.03 | 0.03 | NEMSOK - Kód prvku: OV00.02.0001; Podlaží: 1.NP
 | Půdorys 1.NP | FLOOR | KRYCÍ ROŠT ANGLICKÉHO DVORKU | yes | Rošt (Atribut objektu!) | Zámečnické práce | KRYCÍ ROŠT ANGLICKÉHO DVORKU | 1464Des1096156059 | m2 | Deska | NEW | no | 0.668 | 1.06 | 0.668 | 0.02 | 3.38 | 0.02 | 0.63 | 0.03 | NEMSOK - Kód prvku: OV00.02.0001; Podlaží: 1.NP
 | Půdorys 1.NP | FLOOR | KRYCÍ ROŠT ANGLICKÉHO DVORKU | yes | Rošt (Atribut objektu!) | Zámečnické práce | KRYCÍ ROŠT ANGLICKÉHO DVORKU | 1464Des1096174407 | m2 | Deska | NEW | no | 0.668 | 1.06 | 0.668 | 0.02 | 3.38 | 0.02 | 0.63 | 0.03 | NEMSOK - Kód prvku: OV00.02.0001; Podlaží: 1.NP
 | Půdorys 1.NP | FLOOR | POHLEDOVY BETON | yes | Betonová deska (Atribut objektu!) | Betonářské práce | POHLEDOVY BETON | 1464Des1096289717 | m3 | Obrubník | NEW | no | 1.048 | 0.664 | 1.05 | 0.21 | 6.994 | 0.21 | 1.577 | 0.2 | NEMSOK - Kód prvku: SL07.03.0001; Podlaží: 1.NP; Funkce (venkovní): Ano
 | Půdorys 1.NP | FLOOR | POHLEDOVY BETON | yes | Betonová deska (Atribut objektu!) | Betonářské práce | POHLEDOVY BETON | 1464Des1096289677 | m3 | Obrubník | NEW | no | 0.705 | 0.672 | 0.703 | 0.141 | 4.708 | 0.141 | 1.05 | 0.2 | NEMSOK - Kód prvku: SL07.03.0002; Podlaží: 1.NP; Funkce (venkovní): Ano
 | Půdorys 1.NP | FLOOR | Pult - sesterna | yes | 0 | Truhlářské práce | Pult - sesterna | 1465Des0000024879 | m2 | Deska | NEW |  | 9.596 | 1.476 | 9.595 | 7.197 | 34.205 | 7.197 | 6.5 | 0.75 | NEMSOK - Kód prvku: TV00.03.0006; Číslo místnosti: 1.09; Podlaží: 1.NP
 | Půdorys 1.NP | FLOOR | Pult - sesterna | yes | 0 | Truhlářské práce | Pult - sesterna | 1465Des0000024881 | m2 | Deska | NEW | no | 4.643 | 0.621 | 4.643 | 5.571 | 29.819 | 5.571 | 7.473 | 1.2 | NEMSOK - Kód prvku: TV00.03.0006; Číslo místnosti: 1.09; Podlaží: 1.NP
 | Půdorys 1.NP | FLOOR | ZELEZOBETONOVÁ KCE | yes | Betonová deska (Atribut objektu!) | Betonářské práce | ZELEZOBETONOVÁ KCE | 1466Des0000000004 | m3 | Deska | NEW | no | 113.516 | 7.194 | 112.763 | 22.703 | 55.75 | 22.552 | 15.78 | 0.2 | NEMSOK - Kód prvku: SK01.03.0002; Třída pevnosti ocele: B500B; Stupeň vyztužení: 120; Třída pevnosti betonu: C25/30-XC1; Krytí výztuže: 25mm; Podlaží: 1.NP; Požární odolnost: A
 | Půdorys 1.NP | FLOOR | PIR | yes | Izolace střechy (Atribut objektu!) | Izolace tepelné | PIR | 1466Des0000000014 | m3 | Deska | NEW | no | 101.583 | 6.605 | 100.83 | 26.411 | 54.05 | 26.215 | 15.38 | 0.26 | NEMSOK - Kód prvku: TI05.03.1001; Požární odolnost: E; Systém kotvení: Mechanicky kotvený + přitížený; Součinitel prostupu tepla: 0.022; Součinitel difúzního odporu: 150; Způsob spojení vrstev: Lepený + mechanicky kotvený
 | Půdorys 1.NP | FLOOR | PIR | yes | Izolace střechy (Atribut objektu!) | Izolace tepelné | PIR | 1466Des0000000017 | m3 | Deska | NEW | no | 67.24 | 9.1 | 67.187 | 17.482 | 36.3 | 17.469 | 7.389 | 0.26 | NEMSOK - Kód prvku: TI05.03.1001; Požární odolnost: E; Systém kotvení: Mechanicky kotvený + přitížený; Součinitel prostupu tepla: 0.022; Součinitel difúzního odporu: 150; Způsob spojení vrstev: Lepený + mechanicky kotvený
 | Půdorys 1.NP | FLOOR | ZELEZOBETONOVÁ KCE | yes | Betonová deska (Atribut objektu!) | Betonářské práce | ZELEZOBETONOVÁ KCE | 1466Des0000000028 | m3 | Deska | NEW | no | 641.399 | 2.18 | 637.049 | 160.35 | 133.96 | 159.262 | 294.22 | 0.25 | NEMSOK - Kód prvku: SK01.03.0001; Třída pevnosti ocele: B500B; Stupeň vyztužení: 150; Třída pevnosti betonu: C25/30-XC1; Krytí výztuže: 25mm; Podlaží: 1.NP; Požární odolnost: A
 | Půdorys 1.NP | FLOOR | PIR | yes | Izolace střechy (Atribut objektu!) | Izolace tepelné | PIR | 1466Des0000000347 | m3 | Deska | NEW | no | 605.324 | 43.8 | 602.734 | 157.384 | 134.66 | 156.711 | 13.82 | 0.26 | NEMSOK - Kód prvku: TI05.03.1001; Požární odolnost: E; Systém kotvení: Mechanicky kotvený + přitížený; Součinitel prostupu tepla: 0.022; Součinitel difúzního odporu: 150; Způsob spojení vrstev: Lepený + mechanicky kotvený
 | Půdorys 1.NP | FLOOR | MINERÁLNÍ VATA | yes | Izolace střechy (Atribut objektu!) | Izolace tepelné | MINERÁLNÍ VATA | 1466Des0000000446 | m3 | Deska | NEW | no | 138.84 | 7.8 | 138.84 | 16.661 | 51.2 | 16.661 | 17.8 | 0.12 | NEMSOK - Kód prvku: TI06.03.1001; Požární odolnost: A1; Systém kotvení: Lepený + mechanicky kotvený; Součinitel prostupu tepla: 0.036; Součinitel difúzního odporu: 1; Způsob spojení vrstev: Lepený + mechanicky kotvený
 | Půdorys 1.NP | FLOOR | Demontáž a montáž kazetového pod | yes | Stávající kazetový podhled | Suché stavební práce | Demontáž a montáž kazetového pod | 1468Des0000002325 | m3 | Deska | EXISTING | no | 2.203 | 0.787 | 2.204 | 0.11 | 7.44 | 0.11 | 2.8 | 0.05
 | Půdorys 1.NP | FLOOR | Demontáž a montáž kazetového pod | yes | Stávající kazetový podhled | Suché stavební práce | Demontáž a montáž kazetového pod | 1468Des0000002370 | m3 | Deska | EXISTING |  | 15.344 | 0.872 | 15.345 | 0.767 | 54.3 | 0.767 | 17.6 | 0.05
 | Půdorys 1.NP | FLOOR | Demontáž a montáž kazetového pod | yes | Stávající kazetový podhled | Suché stavební práce | Demontáž a montáž kazetového pod | 1468Des0000002373 | m3 | Deska | EXISTING |  | 4.058 | 3.775 | 4.058 | 0.203 | 9.7 | 0.203 | 1.075 | 0.05
 | Půdorys 1.NP | FLOOR | Kazetový podhled bílý 0,6×0,6 | yes | RASTR 1 | Suché stavební práce | Kazetový podhled bílý 0,6×0,6 | 1468Des0000000008 | m3 | Deska | NEW | no | 38.845 | 3.035 | 38.846 | 1.942 | 37 | 1.942 | 12.8 | 0.05 | NEMSOK - Kód prvku: PH03.03.1001; Požární odolnost: bez požadavku; Únosnost bodová: 0.5 kg; Výška svěšení: 450.00
 | Půdorys 1.NP | FLOOR | Kazetový podhled bílý 0,6×0,6 | yes | RASTR 1 | Suché stavební práce | Kazetový podhled bílý 0,6×0,6 | 1468Des0000000017 | m3 | Deska | NEW | no | 19.372 | 3.15 | 19.373 | 0.969 | 18.6 | 0.969 | 6.15 | 0.05 | NEMSOK - Kód prvku: PH03.03.1002; Požární odolnost: bez požadavku; Únosnost bodová: 0.5 kg; Výška svěšení: 650.00
 | Půdorys 1.NP | FLOOR | Kazetový podhled bílý 0,6×0,6 | yes | RASTR 2 | Suché stavební práce | Kazetový podhled bílý 0,6×0,6 | 1468Des0000000020 | m3 | Deska | NEW | no | 6.698 | 2.05 | 6.698 | 0.335 | 12.73 | 0.335 | 3.267 | 0.05 | NEMSOK - Kód prvku: PH03.03.2001; Požární odolnost: bez požadavku; Únosnost bodová: 0.5 kg; Výška svěšení: 650.00
 | Půdorys 1.NP | FLOOR | Kazetový podhled bílý 0,6×0,6 | yes | RASTR 2 | Suché stavební práce | Kazetový podhled bílý 0,6×0,6 | 1468Des0000000023 | m3 | Deska | NEW | no | 4.804 | 3.35 | 4.804 | 0.24 | 11.58 | 0.24 | 1.434 | 0.05 | NEMSOK - Kód prvku: PH03.03.2002; Požární odolnost: bez požadavku; Únosnost bodová: 0.5 kg; Výška svěšení: 650.00
 | Půdorys 1.NP | FLOOR | Kazetový podhled bílý 0,6×0,6 | yes | RASTR 2 | Suché stavební práce | Kazetový podhled bílý 0,6×0,6 | 1468Des0000000026 | m3 | Deska | NEW | no | 3.479 | 1.85 | 3.479 | 0.174 | 9.58 | 0.174 | 1.881 | 0.05 | NEMSOK - Kód prvku: PH03.03.2003; Požární odolnost: bez požadavku; Únosnost bodová: 0.5 kg; Výška svěšení: 650.00
 | Půdorys 1.NP | FLOOR | Kazetový podhled bílý 0,6×0,6 | yes | RASTR 2 | Suché stavební práce | Kazetový podhled bílý 0,6×0,6 | 1468Des0000000029 | m3 | Deska | NEW | no | 2.063 | 1.65 | 2.063 | 0.103 | 5.8 | 0.103 | 1.25 | 0.05 | NEMSOK - Kód prvku: PH03.03.2004; Požární odolnost: bez požadavku; Únosnost bodová: 0.5 kg; Výška svěšení: 650.00
 | Půdorys 1.NP | FLOOR | Kazetový podhled bílý 0,6×0,6 | yes | RASTR 2 | Suché stavební práce | Kazetový podhled bílý 0,6×0,6 | 1468Des0000000032 | m3 | Deska | NEW | no | 1.328 | 0.9 | 1.328 | 0.066 | 4.75 | 0.066 | 1.475 | 0.05 | NEMSOK - Kód prvku: PH03.03.2005; Požární odolnost: bez požadavku; Únosnost bodová: 0.5 kg; Výška svěšení: 650.00
 | Půdorys 1.NP | FLOOR | Kazetový podhled bílý 0,6×0,6 | yes | RASTR 2 | Suché stavební práce | Kazetový podhled bílý 0,6×0,6 | 1468Des0000000035 | m3 | Deska | NEW | no | 2.219 | 1.325 | 2.219 | 0.111 | 6 | 0.111 | 1.675 | 0.05 | NEMSOK - Kód prvku: PH03.03.2006; Požární odolnost: bez požadavku; Únosnost bodová: 0.5 kg; Výška svěšení: 650.00
 | Půdorys 1.NP | FLOOR | Kazetový podhled bílý 0,6×0,6 | yes | RASTR 2 | Suché stavební práce | Kazetový podhled bílý 0,6×0,6 | 1468Des0000000038 | m3 | Deska | NEW | no | 2.275 | 1.264 | 2.275 | 0.114 | 6.25 | 0.114 | 1.8 | 0.05 | NEMSOK - Kód prvku: PH03.03.2007; Požární odolnost: bez požadavku; Únosnost bodová: 0.5 kg; Výška svěšení: 650.00
 | Půdorys 1.NP | FLOOR | Kazetový podhled bílý 0,6×0,6 | yes | RASTR 2 | Suché stavební práce | Kazetový podhled bílý 0,6×0,6 | 1468Des0000000041 | m3 | Deska | NEW | no | 3.41 | 1.75 | 3.41 | 0.171 | 9.53 | 0.171 | 1.949 | 0.05 | NEMSOK - Kód prvku: PH03.03.2008; Požární odolnost: bez požadavku; Únosnost bodová: 0.5 kg; Výška svěšení: 650.00
 | Půdorys 1.NP | FLOOR | Kazetový podhled hyg. 0,6×0,6 | yes | RASTR 3 | Suché stavební práce | Kazetový podhled hyg. 0,6×0,6 | 1468Des0000000044 | m3 | Deska | NEW | no | 21.515 | 4.138 | 21.515 | 1.076 | 20.64 | 1.076 | 5.2 | 0.05 | NEMSOK - Kód prvku: PH03.03.3001; Požární odolnost: bez požadavku; Únosnost bodová: 0.5 kg; Výška svěšení: 600.00
 | Půdorys 1.NP | FLOOR | Kazetový podhled hyg. 0,6×0,6 | yes | RASTR 3 | Suché stavební práce | Kazetový podhled hyg. 0,6×0,6 | 1468Des0000000047 | m3 | Deska | NEW | no | 25.261 | 3.379 | 25.262 | 1.263 | 26.24 | 1.263 | 7.475 | 0.05 | NEMSOK - Kód prvku: PH03.03.3002; Požární odolnost: bez požadavku; Únosnost bodová: 0.5 kg; Výška svěšení: 650.00
 | Půdorys 1.NP | FLOOR | Kazetový podhled bílý 0,6×0,6 | yes | RASTR 1 | Suché stavební práce | Kazetový podhled bílý 0,6×0,6 | 1468Des0000000050 | m3 | Deska | NEW | no | 36.828 | 3.808 | 36.828 | 1.841 | 33.64 | 1.841 | 9.67 | 0.05 | NEMSOK - Kód prvku: PH03.03.1003; Požární odolnost: bez požadavku; Únosnost bodová: 0.5 kg; Výška svěšení: 600.00
 | Půdorys 1.NP | FLOOR | Kazetový podhled hyg. 0,6×0,6 | yes | RASTR 3 | Suché stavební práce | Kazetový podhled hyg. 0,6×0,6 | 1468Des0000000053 | m3 | Deska | NEW | no | 24.902 | 3.35 | 24.903 | 1.245 | 22.8 | 1.245 | 7.434 | 0.05 | NEMSOK - Kód prvku: PH03.03.3003; Požární odolnost: bez požadavku; Únosnost bodová: 0.5 kg; Výška svěšení: 600.00
 | Půdorys 1.NP | FLOOR | Kazetový podhled hyg. 0,6×0,6 | yes | RASTR 3 | Suché stavební práce | Kazetový podhled hyg. 0,6×0,6 | 1468Des0000000056 | m3 | Deska | NEW | no | 12.41 | 3.65 | 12.41 | 0.62 | 14.1 | 0.62 | 3.4 | 0.05 | NEMSOK - Kód prvku: PH03.03.3004; Požární odolnost: bez požadavku; Únosnost bodová: 0.5 kg; Výška svěšení: 600.00
 | Půdorys 1.NP | FLOOR | Kazetový podhled hyg. 0,6×0,6 | yes | RASTR 3 | Suché stavební práce | Kazetový podhled hyg. 0,6×0,6 | 1468Des0000000059 | m3 | Deska | NEW | no | 12.41 | 3.4 | 12.41 | 0.62 | 14.1 | 0.62 | 3.65 | 0.05 | NEMSOK - Kód prvku: PH03.03.3005; Požární odolnost: bez požadavku; Únosnost bodová: 0.5 kg; Výška svěšení: 600.00
 | Půdorys 1.NP | FLOOR | Kazetový podhled hyg. 0,6×0,6 | yes | RASTR 3 | Suché stavební práce | Kazetový podhled hyg. 0,6×0,6 | 1468Des0000000062 | m3 | Deska | NEW | no | 12.41 | 3.4 | 12.41 | 0.62 | 14.1 | 0.62 | 3.65 | 0.05 | NEMSOK - Kód prvku: PH03.03.3006; Požární odolnost: bez požadavku; Únosnost bodová: 0.5 kg; Výška svěšení: 600.00
 | Půdorys 1.NP | FLOOR | Kazetový podhled hyg. 0,6×0,6 | yes | RASTR 3 | Suché stavební práce | Kazetový podhled hyg. 0,6×0,6 | 1468Des0000000065 | m3 | Deska | NEW | no | 12.41 | 3.4 | 12.41 | 0.62 | 14.1 | 0.62 | 3.65 | 0.05 | NEMSOK - Kód prvku: PH03.03.3007; Požární odolnost: bez požadavku; Únosnost bodová: 0.5 kg; Výška svěšení: 600.00
 | Půdorys 1.NP | FLOOR | Kazetový podhled hyg. 0,6×0,6 | yes | RASTR 3 | Suché stavební práce | Kazetový podhled hyg. 0,6×0,6 | 1468Des0000000068 | m3 | Deska | NEW | no | 11.741 | 3.217 | 11.741 | 0.587 | 13.422 | 0.587 | 3.65 | 0.05 | NEMSOK - Kód prvku: PH03.03.3008; Požární odolnost: bez požadavku; Únosnost bodová: 0.5 kg; Výška svěšení: 600.00
 | Půdorys 1.NP | FLOOR | Kazetový podhled bílý 0,6×0,6 | yes | RASTR 2 | Suché stavební práce | Kazetový podhled bílý 0,6×0,6 | 1468Des0000000071 | m3 | Deska | NEW | no | 12.015 | 4.45 | 12.015 | 0.601 | 14.3 | 0.601 | 2.7 | 0.05 | NEMSOK - Kód prvku: PH03.03.2009; Požární odolnost: bez požadavku; Únosnost bodová: 0.5 kg; Výška svěšení: 600.00
 | Půdorys 1.NP | FLOOR | Kazetový podhled hyg. 0,6×0,6 | yes | RASTR 3 | Suché stavební práce | Kazetový podhled hyg. 0,6×0,6 | 1468Des0000000074 | m3 | Deska | NEW | no | 23.562 | 4.033 | 23.561 | 1.178 | 19.854 | 1.178 | 5.842 | 0.05 | NEMSOK - Kód prvku: PH03.03.3009; Požární odolnost: bez požadavku; Únosnost bodová: 0.5 kg; Výška svěšení: 600.00
 | Půdorys 1.NP | FLOOR | Kazetový podhled bílý 0,6×0,6 | yes | RASTR 1 | Suché stavební práce | Kazetový podhled bílý 0,6×0,6 | 1468Des0000000077 | m3 | Deska | NEW | no | 13.239 | 3 | 13.239 | 0.662 | 14.9 | 0.662 | 4.413 | 0.05 | NEMSOK - Kód prvku: PH03.03.1004; Požární odolnost: bez požadavku; Únosnost bodová: 0.5 kg; Výška svěšení: 600.00
 | Půdorys 1.NP | FLOOR | Kazetový podhled bílý 0,6×0,6 | yes | RASTR 1 | Suché stavební práce | Kazetový podhled bílý 0,6×0,6 | 1468Des0000000080 | m3 | Deska | NEW | no | 11.271 | 2.533 | 11.271 | 0.564 | 15.44 | 0.564 | 4.45 | 0.05 | NEMSOK - Kód prvku: PH03.03.1005; Požární odolnost: bez požadavku; Únosnost bodová: 0.5 kg; Výška svěšení: 600.00
 | Půdorys 1.NP | FLOOR | Kazetový podhled bílý 0,6×0,6 | yes | RASTR 2 | Suché stavební práce | Kazetový podhled bílý 0,6×0,6 | 1468Des0000000086 | m3 | Deska | NEW | no | 3.349 | 0.875 | 3.348 | 0.167 | 7.45 | 0.167 | 3.827 | 0.05 | NEMSOK - Kód prvku: PH03.03.2010; Požární odolnost: bez požadavku; Únosnost bodová: 0.5 kg; Výška svěšení: 650.00
 | Půdorys 1.NP | FLOOR | Kazetový podhled bílý 0,6×0,6 | yes | RASTR 2 | Suché stavební práce | Kazetový podhled bílý 0,6×0,6 | 1468Des0000000095 | m3 | Deska | NEW | no | 3.737 | 2.28 | 3.737 | 0.187 | 8.11 | 0.187 | 1.639 | 0.05 | NEMSOK - Kód prvku: PH03.03.2011; Požární odolnost: bez požadavku; Únosnost bodová: 0.5 kg; Výška svěšení: 650.00
 | Půdorys 1.NP | FLOOR | Kazetový podhled bílý 0,6×0,6 | yes | RASTR 2 | Suché stavební práce | Kazetový podhled bílý 0,6×0,6 | 1468Des0000000098 | m3 | Deska | NEW | no | 2.754 | 1.343 | 2.754 | 0.138 | 7.35 | 0.138 | 2.05 | 0.05 | NEMSOK - Kód prvku: PH03.03.2012; Požární odolnost: bez požadavku; Únosnost bodová: 0.5 kg; Výška svěšení: 650.00
 | Půdorys 1.NP | FLOOR | Kazetový podhled bílý 0,6×0,6 | yes | RASTR 1 | Suché stavební práce | Kazetový podhled bílý 0,6×0,6 | 1468Des0000000104 | m3 | Deska | NEW | no | 48.75 | 10.475 | 48.75 | 2.437 | 39.55 | 2.437 | 4.654 | 0.05 | NEMSOK - Kód prvku: PH03.03.1006; Požární odolnost: bez požadavku; Únosnost bodová: 0.5 kg; Výška svěšení: 650.00
 | Půdorys 1.NP | FLOOR | Kazetový podhled bílý 0,6×0,6 | yes | RASTR 2 | Suché stavební práce | Kazetový podhled bílý 0,6×0,6 | 1468Des0000000111 | m3 | Deska | NEW | no | 1.057 | 0.9 | 1.058 | 0.053 | 4.15 | 0.053 | 1.175 | 0.05 | NEMSOK - Kód prvku: PH03.03.2013; Požární odolnost: bez požadavku; Únosnost bodová: 0.5 kg; Výška svěšení: 650.00
 | Půdorys 1.NP | FLOOR | Kazet. podhled do vlhka 0,6×0,6 | yes | RASTR 4 | Suché stavební práce | Kazet. podhled do vlhka 0,6×0,6 | 1468Des0000000120 | m3 | Deska | NEW | no | 16.342 | 4.47 | 16.342 | 0.817 | 17.94 | 0.817 | 3.656 | 0.05 | NEMSOK - Kód prvku: PH03.03.4001; Požární odolnost: bez požadavku; Únosnost bodová: 0.5 kg; Výška svěšení: 650.00
 | Půdorys 1.NP | FLOOR | Kazet. podhled do vlhka 0,6×0,6 | yes | RASTR 4 | Suché stavební práce | Kazet. podhled do vlhka 0,6×0,6 | 1468Des0000000127 | m3 | Deska | NEW | no | 18.302 | 2.448 | 18.302 | 0.915 | 22.19 | 0.915 | 7.475 | 0.05 | NEMSOK - Kód prvku: PH03.03.4002; Požární odolnost: bez požadavku; Únosnost bodová: 0.5 kg; Výška svěšení: 650.00
 | Půdorys 1.NP | FLOOR | Kazetový podhled bílý 0,6×0,6 | yes | RASTR 2 | Suché stavební práce | Kazetový podhled bílý 0,6×0,6 | 1468Des0000000130 | m3 | Deska | NEW | no | 28.366 | 4.246 | 28.369 | 1.418 | 26.26 | 1.418 | 6.68 | 0.05 | NEMSOK - Kód prvku: PH03.03.2014; Požární odolnost: bez požadavku; Únosnost bodová: 0.5 kg; Výška svěšení: 650.00
 | Půdorys 1.NP | FLOOR | Kazetový podhled bílý 0,6×0,6 | yes | RASTR 2 | Suché stavební práce | Kazetový podhled bílý 0,6×0,6 | 1468Des0000000133 | m3 | Deska | NEW | no | 15.989 | 3.15 | 15.989 | 0.799 | 18.29 | 0.799 | 5.076 | 0.05 | NEMSOK - Kód prvku: PH03.03.2015; Požární odolnost: bez požadavku; Únosnost bodová: 0.5 kg; Výška svěšení: 650.00
 | Půdorys 1.NP | FLOOR | Kazetový podhled hyg. 0,6×0,6 | yes | RASTR 3 | Suché stavební práce | Kazetový podhled hyg. 0,6×0,6 | 1468Des0000000136 | m3 | Deska | NEW | no | 150.016 | 8.452 | 150.016 | 7.501 | 77.551 | 7.501 | 17.75 | 0.05 | NEMSOK - Kód prvku: PH03.03.3010; Požární odolnost: bez požadavku; Únosnost bodová: 0.5 kg; Výška svěšení: 600.00
 | Půdorys 1.NP | FLOOR | Kazet. podhled do vlhka 0,6×0,6 | yes | RASTR 4 | Suché stavební práce | Kazet. podhled do vlhka 0,6×0,6 | 1468Des0000000159 | m3 | Deska | NEW | no | 1.95 | 1.95 | 1.95 | 0.098 | 5.9 | 0.098 | 1 | 0.05 | NEMSOK - Kód prvku: PH03.03.4003; Požární odolnost: bez požadavku; Únosnost bodová: 0.5 kg; Výška svěšení: 650.00
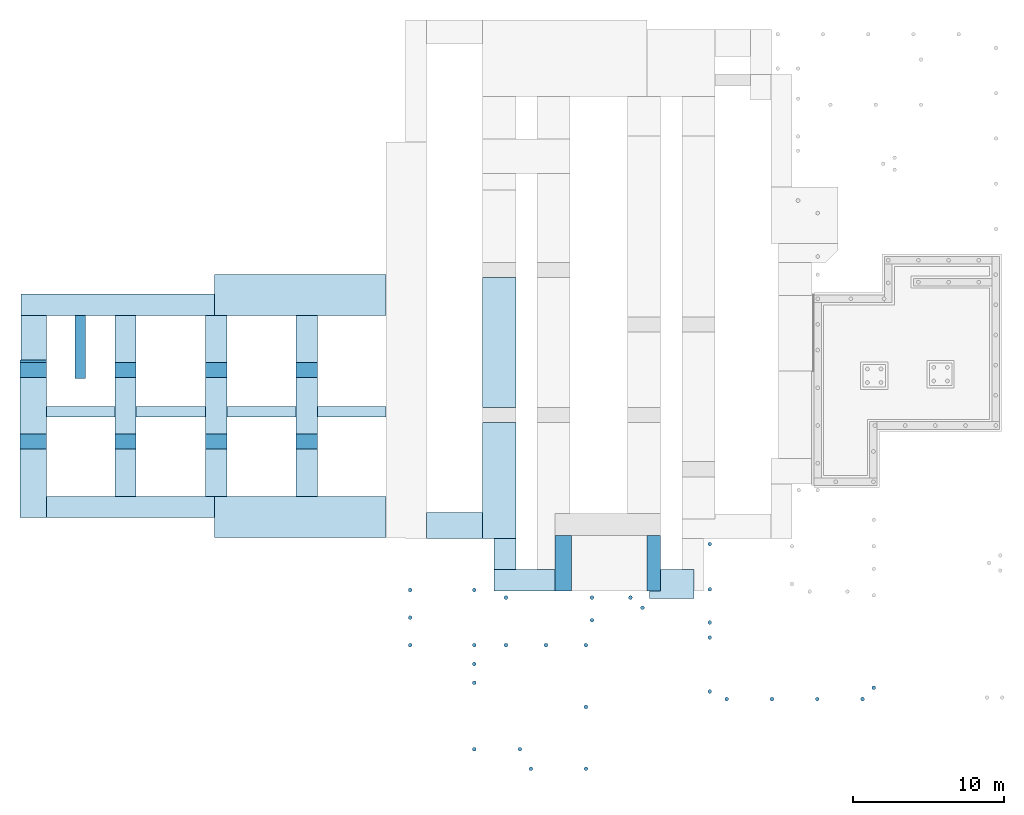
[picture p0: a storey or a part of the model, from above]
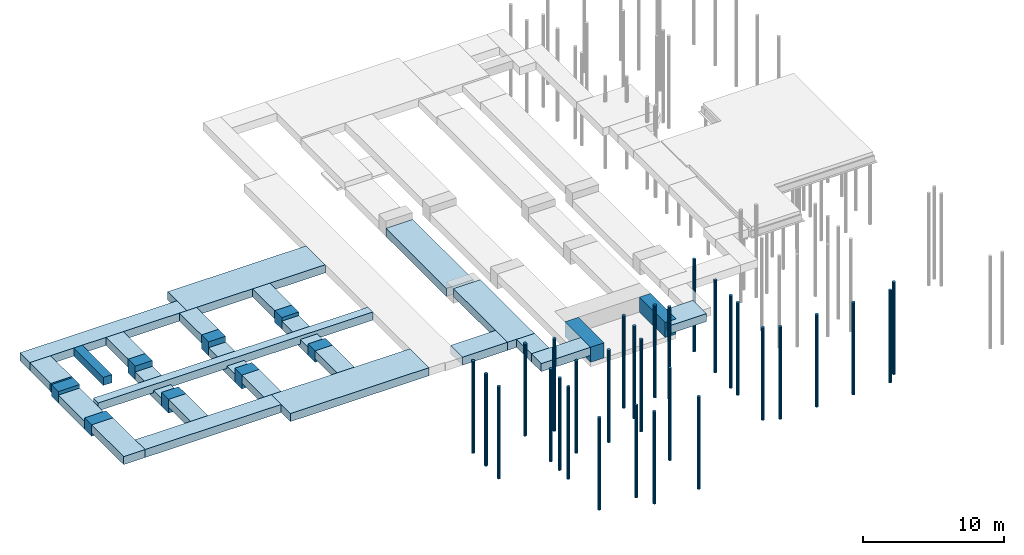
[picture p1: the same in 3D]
Properties of the parts of a building model (IFC4), part 22 of 45

# IfcSlab (566)
Name | In | PredefinedType | Material | 2D interakce | Krátký_text | Práce | Materiál | Allright_Stavebni_dil_ID | Jednotka | Název_objektu | Status | LoadBearing | GrossArea (m2) | Depth (m) | NetArea (m2) | GrossVolume (m3) | Perimeter (m) | NetVolume (m3) | Length (m) | Width (m)
 | Půdorys 1.NP | FLOOR | Kazetový podhled bílý 0,6×0,6 | yes | RASTR 2 | Suché stavební práce | Kazetový podhled bílý 0,6×0,6 | 1468Des0000000162 | m3 | Deska | NEW | no | 2.291 | 1.175 | 2.291 | 0.115 | 6.25 | 0.115 | 1.95 | 0.05 | NEMSOK - Kód prvku: PH03.03.2016; Požární odolnost: bez požadavku; Únosnost bodová: 0.5 kg; Výška svěšení: 650.00
 | Půdorys 1.NP | FLOOR | Kazetový podhled bílý 0,6×0,6 | yes | RASTR 2 | Suché stavební práce | Kazetový podhled bílý 0,6×0,6 | 1468Des0000000165 | m3 | Deska | NEW | no | 2.21 | 1.9 | 2.21 | 0.11 | 6.4 | 0.11 | 1.163 | 0.05 | NEMSOK - Kód prvku: PH03.03.2017; Požární odolnost: bez požadavku; Únosnost bodová: 0.5 kg; Výška svěšení: 650.00
 | Půdorys 1.NP | FLOOR | Kazetový podhled bílý 0,6×0,6 | yes | RASTR 1 | Suché stavební práce | Kazetový podhled bílý 0,6×0,6 | 1468Des0000000168 | m3 | Deska | NEW | no | 22.13 | 3.625 | 22.131 | 1.107 | 20.01 | 1.107 | 6.105 | 0.05 | NEMSOK - Kód prvku: PH03.03.1007; Požární odolnost: bez požadavku; Únosnost bodová: 0.5 kg; Výška svěšení: 650.00
 | Půdorys 1.NP | FLOOR | Kazetový podhled bílý 0,6×0,6 | yes | RASTR 2 | Suché stavební práce | Kazetový podhled bílý 0,6×0,6 | 1468Des0000000228 | m3 | Deska | NEW | no | 5.011 | 2.25 | 5.012 | 0.251 | 10.25 | 0.251 | 2.227 | 0.05 | NEMSOK - Kód prvku: PH03.03.2018; Požární odolnost: bez požadavku; Únosnost bodová: 0.5 kg; Výška svěšení: 650.00
 | Půdorys 1.NP | FLOOR | Kazetový podhled bílý 0,6×0,6 | yes | RASTR 1 | Suché stavební práce | Kazetový podhled bílý 0,6×0,6 | 1468Des0000001093 | m3 | Deska | NEW | no | 55.44 | 7.8 | 55.44 | 2.772 | 31.2 | 2.772 | 7.108 | 0.05 | NEMSOK - Kód prvku: PH03.03.1008; Požární odolnost: bez požadavku; Únosnost bodová: 0.5 kg; Výška svěšení: 600.00
 | Půdorys 1.NP | FLOOR | SDK hladký bílý | yes | SDK | Suché stavební práce | SDK hladký bílý | 1468Des0000001125 | m3 | Deska | NEW | no | 13.248 | 6.9 | 13.248 | 0.662 | 17.64 | 0.662 | 1.92 | 0.05 | NEMSOK - Kód prvku: PH01.03.0001; Požární odolnost: bez požadavku; Únosnost bodová: 0.5 kg; Výška svěšení: 600.00
 | Půdorys 1.NP | FLOOR | SDK hladký bílý | yes | SDK | Suché stavební práce | SDK hladký bílý | 1468Des0000001128 | m3 | Deska | NEW | no | 20.648 | 2.101 | 20.648 | 1.032 | 69.74 | 1.032 | 9.83 | 0.05 | NEMSOK - Kód prvku: PH01.03.0002; Požární odolnost: bez požadavku; Únosnost bodová: 0.5 kg; Výška svěšení: 600.00
 | Půdorys 1.NP | FLOOR | SDK hladký bílý | yes | SDK | Suché stavební práce | SDK hladký bílý | 1468Des0000001498 | m3 | Deska | NEW | no | 57.76 | 7.224 | 57.761 | 2.888 | 32.2 | 2.888 | 7.995 | 0.05 | NEMSOK - Kód prvku: PH01.03.0003; Požární odolnost: bez požadavku; Únosnost bodová: 0.5 kg; Výška svěšení: 350.00 mm
 | Půdorys 1.NP | FLOOR | SDK hladký bílý | yes | SDK | Suché stavební práce | SDK hladký bílý | 1468Des0000001547 | m3 | Deska | NEW | no | 10.694 | 3.625 | 10.694 | 0.535 | 13.15 | 0.535 | 2.95 | 0.05 | NEMSOK - Kód prvku: PH01.03.0004; Požární odolnost: bez požadavku; Únosnost bodová: 0.5 kg; Výška svěšení: 350.00 mm
 | Půdorys 1.NP | FLOOR | SDK hladký bílý | yes | SDK | Suché stavební práce | SDK hladký bílý | 1468Des0000001944 | m3 | Deska | NEW | no | 2.148 | 4.475 | 2.148 | 0.107 | 9.91 | 0.107 | 0.48 | 0.05 | NEMSOK - Kód prvku: PH01.03.0005; Požární odolnost: bez požadavku; Únosnost bodová: 0.5 kg; Výška svěšení: 800.0 mm
 | Půdorys 1.NP | FLOOR | Kazetový podhled bílý 0,6×0,6 | yes | RASTR 2 | Suché stavební práce | Kazetový podhled bílý 0,6×0,6 | 1468Des0000001965 | m3 | Deska | NEW | no | 11.862 | 2.72 | 11.862 | 0.593 | 14.84 | 0.593 | 4.361 | 0.05 | NEMSOK - Kód prvku: PH03.03.2019; Požární odolnost: bez požadavku; Únosnost bodová: 0.5 kg; Výška svěšení: 650.00
 | Půdorys 1.NP | FLOOR | Kazetový podhled hyg. 0,6×0,6 | yes | RASTR 3 | Suché stavební práce | Kazetový podhled hyg. 0,6×0,6 | 1468Des0000001997 | m3 | Deska | NEW | no | 13.915 | 2.3 | 13.915 | 0.696 | 16.7 | 0.696 | 6.05 | 0.05 | NEMSOK - Kód prvku: PH03.03.3012; Požární odolnost: bez požadavku; Únosnost bodová: 0.5 kg; Výška svěšení: 450.00
 | Půdorys 1.NP | FLOOR | Kazetový podhled bílý 0,6×0,6 | yes | RASTR 1 | Suché stavební práce | Kazetový podhled bílý 0,6×0,6 | 1468Des0000002039 | m3 | Deska | NEW | no | 9.96 | 2.4 | 9.96 | 0.498 | 13.15 | 0.498 | 4.15 | 0.05 | NEMSOK - Kód prvku: PH03.03.1009; Požární odolnost: bez požadavku; Únosnost bodová: 0.5 kg; Výška svěšení: 250.0 mm
 | Půdorys 1.NP | FLOOR | SDK hladký bílý | yes | SDK | Suché stavební práce | SDK hladký bílý | 1468Des0000002088 | m3 | Deska | NEW | no | 1.575 | 1.575 | 1.575 | 0.079 | 5.15 | 0.079 | 1 | 0.05 | NEMSOK - Kód prvku: PH01.03.0006; Požární odolnost: bez požadavku; Únosnost bodová: 0.5 kg; Výška svěšení: 650.00
 | Půdorys 1.NP | FLOOR | SDK hladký bílý | yes | SDK | Suché stavební práce | SDK hladký bílý | 1468Des0000002091 | m3 | Deska | NEW | no | 2.345 | 1.675 | 2.345 | 0.117 | 6.15 | 0.117 | 1.4 | 0.05 | NEMSOK - Kód prvku: PH01.03.0007; Požární odolnost: bez požadavku; Únosnost bodová: 0.5 kg; Výška svěšení: 650.00
 | Půdorys 1.NP | FLOOR | SDK hladký bílý | yes | SDK | Suché stavební práce | SDK hladký bílý | 1468Des0000002094 | m3 | Deska | NEW | no | 4.236 | 1.695 | 4.237 | 0.212 | 8.6 | 0.212 | 2.5 | 0.05 | NEMSOK - Kód prvku: PH01.03.0008; Požární odolnost: bez požadavku; Únosnost bodová: 0.5 kg; Výška svěšení: 650.00
 | Půdorys 1.NP | FLOOR | Kazet. podhled do vlhka 0,6×0,6 | yes | RASTR 4 | Suché stavební práce | Kazet. podhled do vlhka 0,6×0,6 | 1468Des0000002170 | m3 | Deska | NEW | no | 1.63 | 1.6 | 1.63 | 0.081 | 5.35 | 0.081 | 1.019 | 0.05 | NEMSOK - Kód prvku: PH03.03.4004; Požární odolnost: bez požadavku; Únosnost bodová: 0.5 kg; Výška svěšení: 650.00
 | Půdorys 1.NP | FLOOR | Kazet. podhled do vlhka 0,6×0,6 | yes | RASTR 4 | Suché stavební práce | Kazet. podhled do vlhka 0,6×0,6 | 1468Des0000002208 | m3 | Deska | NEW | no | 1.73 | 2.075 | 1.73 | 0.087 | 5.95 | 0.087 | 0.834 | 0.05 | NEMSOK - Kód prvku: PH03.03.4005; Požární odolnost: bez požadavku; Únosnost bodová: 0.5 kg; Výška svěšení: 650.00
 | Půdorys 1.NP | FLOOR | Kazetový podhled bílý 0,6×0,6 | yes | RASTR 2 | Suché stavební práce | Kazetový podhled bílý 0,6×0,6 | 1468Des0000002256 | m3 | Deska | NEW | no | 2.913 | 1.5 | 2.913 | 0.146 | 7.25 | 0.146 | 1.942 | 0.05 | NEMSOK - Kód prvku: PH03.03.2020; Požární odolnost: bez požadavku; Únosnost bodová: 0.5 kg; Výška svěšení: 650.00
 | Půdorys 1.NP | FLOOR | Kazetový podhled bílý 0,6×0,6 | yes | RASTR 2 | Suché stavební práce | Kazetový podhled bílý 0,6×0,6 | 1468Des0000002332 | m3 | Deska | NEW | no | 5.206 | 2.975 | 5.206 | 0.26 | 9.45 | 0.26 | 1.75 | 0.05 | NEMSOK - Kód prvku: PH03.03.2021; Požární odolnost: bez požadavku; Únosnost bodová: 0.5 kg; Výška svěšení: 850.0 mm
 | Půdorys 1.NP | FLOOR | Kazetový podhled hyg. 0,6×0,6 | yes | RASTR 3 | Suché stavební práce | Kazetový podhled hyg. 0,6×0,6 | 1468Des0000002473 | m3 | Deska | NEW | no | 12.559 | 1.763 | 12.559 | 0.628 | 17.8 | 0.628 | 7.125 | 0.05 | NEMSOK - Kód prvku: PH03.03.3011; Požární odolnost: bez požadavku; Únosnost bodová: 0.5 kg; Výška svěšení: 450.00
 | Půdorys 2.NP | FLOOR | VĚNEC | yes | Betonová deska (Atribut objektu!) | Betonářské práce | VĚNEC | 1554Des0000000622 | m3 | Deska | EXISTING | yes | 7.597 | 1.07 | 7.597 | 1.899 | 16.34 | 1.899 | 7.1 | 0.25
 | Půdorys 2.NP | FLOOR | PZD | yes | Betonová deska (Atribut objektu!) | Betonářské práce | PZD | 1554Des0000000616 | m3 | Deska | EXISTING | yes | 31.746 | 2.2 | 31.646 | 7.937 | 33.26 | 7.912 | 14.43 | 0.25
 | Půdorys 2.NP | FLOOR | RZT | yes | Betonová deska (Atribut objektu!) | Betonářské práce | RZT | 1554Des0000000591 | m3 | Deska | EXISTING | yes | 8.4 | 6 | 8.4 | 2.1 | 14.8 | 2.1 | 1.4 | 0.25
 | Půdorys 2.NP | FLOOR | DZH | yes | Betonová deska (Atribut objektu!) | Betonářské práce | DZH | 1554Des0000000566 | m3 | Deska | EXISTING | yes | 5.44 | 3.4 | 5.44 | 1.36 | 10 | 1.36 | 1.6 | 0.25
 | Půdorys 2.NP | FLOOR | PZD | yes | Betonová deska (Atribut objektu!) | Betonářské práce | PZD | 1554Des0000000561 | m3 | Deska | EXISTING | yes | 12.98 | 5.9 | 12.98 | 3.245 | 16.2 | 3.245 | 2.2 | 0.25
 | Půdorys 2.NP | FLOOR | RZT | yes | Betonová deska (Atribut objektu!) | Betonářské práce | RZT | 1554Des0000000559 | m3 | Deska | EXISTING | yes | 8.26 | 5.9 | 8.26 | 2.065 | 14.6 | 2.065 | 1.4 | 0.25
 | Půdorys 2.NP | FLOOR | RZT | yes | Betonová deska (Atribut objektu!) | Betonářské práce | RZT | 1554Des0000000589 | m3 | Deska | EXISTING | yes | 35.28 | 25.2 | 35.28 | 8.82 | 53.2 | 8.82 | 1.4 | 0.25
 | Půdorys 2.NP | FLOOR | RZT | yes | Betonová deska (Atribut objektu!) | Betonářské práce | RZT | 1554Des0000000593 | m3 | Deska | EXISTING | yes | 8.4 | 6 | 8.4 | 2.1 | 14.8 | 2.1 | 1.4 | 0.25
 | Půdorys 2.NP | FLOOR | PZD | yes | Betonová deska (Atribut objektu!) | Betonářské práce | PZD | 1554Des0000000632 | m3 | Deska | EXISTING | yes | 99.12 | 25.2 | 97.46 | 24.78 | 89.2 | 24.365 | 3.933 | 0.25
 | Půdorys 2.NP | FLOOR | RZT | yes | Betonová deska (Atribut objektu!) | Betonářské práce | RZT | 1554Des0000000608 | m3 | Deska | EXISTING | yes | 16.8 | 12 | 16.8 | 4.2 | 26.8 | 4.2 | 1.4 | 0.25
 | Půdorys 2.NP | FLOOR | PZD | yes | Betonová deska (Atribut objektu!) | Betonářské práce | PZD | 1554Des0000000881 | m3 | Deska | EXISTING | yes | 5.52 | 4.6 | 5.52 | 1.38 | 11.6 | 1.38 | 1.2 | 0.25
 | Půdorys 2.NP | FLOOR | PZD | yes | Betonová deska (Atribut objektu!) | Betonářské práce | PZD | 1554Des0000000876 | m3 | Deska | EXISTING | yes | 5.52 | 4.6 | 5.52 | 1.38 | 11.6 | 1.38 | 1.2 | 0.25
 | Půdorys 2.NP | FLOOR | PZD | yes | Betonová deska (Atribut objektu!) | Betonářské práce | PZD | 1554Des0000000867 | m3 | Deska | EXISTING | yes | 2.64 | 2.2 | 2.64 | 0.66 | 6.8 | 0.66 | 1.2 | 0.25
 | Půdorys 2.NP | FLOOR | RZT | yes | Betonová deska (Atribut objektu!) | Betonářské práce | RZT | 1554Des0000000620 | m3 | Deska | EXISTING | yes | 37.1 | 26.5 | 37.1 | 9.275 | 55.8 | 9.275 | 1.4 | 0.25
 | Půdorys 2.NP | FLOOR | RZT | yes | Betonová deska (Atribut objektu!) | Betonářské práce | RZT | 1554Des0000000537 | m3 | Deska | EXISTING | yes | 37.1 | 26.5 | 37.1 | 9.275 | 55.8 | 9.275 | 1.4 | 0.25
 | Půdorys 2.NP | FLOOR | RZT | yes | Betonová deska (Atribut objektu!) | Betonářské práce | RZT | 1554Des0000000606 | m3 | Deska | EXISTING | yes | 37.1 | 26.5 | 37.1 | 9.275 | 55.8 | 9.275 | 1.4 | 0.25
 | Půdorys 2.NP | FLOOR | RZT | yes | Betonová deska (Atribut objektu!) | Betonářské práce | RZT | 1554Des0000000610 | m3 | Deska | EXISTING | yes | 37.1 | 26.5 | 37.1 | 9.275 | 55.8 | 9.275 | 1.4 | 0.25
 | Půdorys 2.NP | FLOOR | RZT | yes | Betonová deska (Atribut objektu!) | Betonářské práce | RZT | 1554Des0000000578 | m3 | Deska | EXISTING | yes | 35.28 | 25.2 | 35.28 | 8.82 | 53.2 | 8.82 | 1.4 | 0.25
 | Půdorys 2.NP | FLOOR | PZD | yes | Betonová deska (Atribut objektu!) | Betonářské práce | PZD | 1554Des0000000555 | m3 | Deska | EXISTING | yes | 62.66 | 2.8 | 61.85 | 15.665 | 43.5 | 15.463 | 22.379 | 0.25
 | Půdorys 2.NP | FLOOR | PZD | yes | Betonová deska (Atribut objektu!) | Betonářské práce | PZD | 1554Des0000000576 | m3 | Deska | EXISTING | yes | 55.44 | 2.2 | 54.99 | 13.86 | 54.8 | 13.748 | 25.2 | 0.25
 | Půdorys 2.NP | FLOOR | PZD | yes | Betonová deska (Atribut objektu!) | Betonářské práce | PZD | 1554Des0000000604 | m3 | Deska | EXISTING | yes | 99.12 | 25.2 | 97.984 | 24.78 | 86.4 | 24.496 | 3.933 | 0.25
 | Půdorys 2.NP | FLOOR | PZD | yes | Betonová deska (Atribut objektu!) | Betonářské práce | PZD | 1554Des0000000557 | m3 | Deska | EXISTING | yes | 9.345 | 2.67 | 9.345 | 2.336 | 12.34 | 2.336 | 3.5 | 0.25
 | Půdorys 2.NP | FLOOR | RZT | yes | Betonová deska (Atribut objektu!) | Betonářské práce | RZT | 1554Des0000000618 | m3 | Deska | EXISTING | yes | 20.202 | 14.43 | 20.202 | 5.051 | 31.66 | 5.051 | 1.4 | 0.25
 | Půdorys 2.NP | FLOOR | PZD | yes | Betonová deska (Atribut objektu!) | Betonářské práce | PZD | 1554Des0000000290 | m3 | Deska | EXISTING | yes | 66.24 | 4.6 | 65.94 | 16.56 | 38 | 16.485 | 14.4 | 0.25
 | Půdorys 2.NP | FLOOR | RZT | yes | Betonová deska (Atribut objektu!) | Betonářské práce | RZT | 1554Des0000000263 | m3 | Deska | EXISTING | yes | 20.16 | 14.4 | 20.054 | 5.04 | 31.6 | 5.013 | 1.4 | 0.25
 | Půdorys 2.NP | FLOOR | RZT | yes | Betonová deska (Atribut objektu!) | Betonářské práce | RZT | 1554Des0000000281 | m3 | Deska | EXISTING | yes | 20.16 | 14.4 | 20.054 | 5.04 | 31.6 | 5.013 | 1.4 | 0.25
 | Půdorys 2.NP | FLOOR | RZT | yes | Betonová deska (Atribut objektu!) | Betonářské práce | RZT | 1554Des0000000292 | m3 | Deska | EXISTING | yes | 20.16 | 14.4 | 20.054 | 5.04 | 31.6 | 5.013 | 1.4 | 0.25
 | Půdorys 2.NP | FLOOR | PZD | yes | Betonová deska (Atribut objektu!) | Betonářské práce | PZD | 1554Des0000000228 | m3 | Deska | EXISTING | yes | 21.195 | 7.85 | 21.195 | 2.119 | 21.1 | 2.119 | 2.7 | 0.1
 | Půdorys 2.NP | FLOOR | PZD | yes | Betonová deska (Atribut objektu!) | Betonářské práce | PZD | 1554Des0000000231 | m3 | Deska | EXISTING | yes | 6.93 | 3.3 | 6.93 | 0.693 | 10.8 | 0.693 | 2.1 | 0.1
 | Půdorys 2.NP | FLOOR | PZD | yes | Betonová deska (Atribut objektu!) | Betonářské práce | PZD | 1554Des0000000234 | m3 | Deska | EXISTING | yes | 8.75 | 3.5 | 8.75 | 2.187 | 12 | 2.037 | 2.5 | 0.25
 | Půdorys 2.NP | FLOOR | RZT | yes | Betonová deska (Atribut objektu!) | Betonářské práce | RZT | 1554Des0000000248 | m3 | Deska | EXISTING | yes | 20.16 | 14.4 | 20.054 | 5.04 | 31.6 | 5.013 | 1.4 | 0.25
 | Půdorys 2.NP | FLOOR | RZT | yes | Betonová deska (Atribut objektu!) | Betonářské práce | RZT | 1554Des0000000259 | m3 | Deska | EXISTING | yes | 20.16 | 14.4 | 20.054 | 5.04 | 31.6 | 5.013 | 1.4 | 0.25
 | Půdorys 2.NP | FLOOR | PZD | yes | Betonová deska (Atribut objektu!) | Betonářské práce | PZD | 1554Des0000000254 | m3 | Deska | EXISTING | yes | 66.24 | 4.6 | 65.44 | 16.56 | 38 | 16.36 | 14.4 | 0.25
 | Půdorys 2.NP | FLOOR | PZD | yes | Betonová deska (Atribut objektu!) | Betonářské práce | PZD | 1554Des0000000271 | m3 | Deska | EXISTING | yes | 66.24 | 4.6 | 65.93 | 16.56 | 38 | 16.483 | 14.4 | 0.25
 | Půdorys 2.NP | FLOOR | PZD | yes | Betonová deska (Atribut objektu!) | Betonářské práce | PZD | 1554Des0000000278 | m3 | Deska | EXISTING | yes | 66.24 | 4.6 | 65.87 | 16.56 | 38 | 16.468 | 14.4 | 0.25
 | Půdorys 2.NP | FLOOR | ZELEZOBETONOVÁ KCE | yes | Betonová deska (Atribut objektu!) | Betonářské práce | ZELEZOBETONOVÁ KCE | 1554Des0000001426 | m3 | Deska | EXISTING | yes | 3.811 | 1.21 | 3.812 | 1.258 | 8.72 | 1.258 | 3.15 | 0.33
 | Půdorys 2.NP | FLOOR | RZT | yes | Betonová deska (Atribut objektu!) | Betonářské práce | RZT | 1554Des0000000552 | m3 | Deska | EXISTING | yes | 8.68 | 6.2 | 8.68 | 2.17 | 15.2 | 2.17 | 1.4 | 0.25
 | Půdorys 2.NP | FLOOR | RZT | yes | Betonová deska (Atribut objektu!) | Betonářské práce | RZT | 1554Des0000000550 | m3 | Deska | EXISTING | yes | 3.64 | 2.6 | 3.64 | 0.91 | 8 | 0.91 | 1.4 | 0.25
 | Půdorys 2.NP | FLOOR | PZD | yes | Betonová deska (Atribut objektu!) | Betonářské práce | PZD | 1554Des0000000548 | m3 | Deska | EXISTING | yes | 103.6 | 25.2 | 99.772 | 25.9 | 82.8 | 24.943 | 4.111 | 0.25
 | Půdorys 2.NP | FLOOR | PZD | yes | Betonová deska (Atribut objektu!) | Betonářské práce | PZD | 1554Des0000000541 | m3 | Deska | EXISTING | yes | 55.44 | 25.2 | 54.69 | 13.86 | 54.8 | 13.672 | 2.2 | 0.25
11 x  | Půdorys 2.NP | ROOF | ASFALTOVÁ HYDROIZOLACE 0.01 m, II.S2 - KAČÍREK 0.12 m
5 x  | Půdorys 2.NP | ROOF
13 x  | Půdorys 2.NP | ROOF | ASFALTOVÁ HYDROIZOLACE 0.01 m, II.S1 - SOUVRSTVÍ ZELENÉ STŘECHY 0.12 m
20 x  | Půdorys 2.NP | ROOF | ASFALTOVÁ HYDROIZOLACE 0.01 m, SOUVRSTVÍ ZELENÉ STŘECHY 0.12 m
16 x  | Půdorys 2.NP | ROOF | ASFALTOVÁ HYDROIZOLACE 0.01 m, KAČÍREK 0.12 m
 | Půdorys 2.NP | FLOOR | SPÁDOVÉ KLÍNY PIR 3% | yes | Spádové klíny (Atribut objektu!) | Izolace tepelné | SPÁDOVÉ KLÍNY PIR 3% | 1564Des0000001951 | m3 | Deska | NEW | no | 0.25 | 0.5 | 0.25 | 0.005 | 2 | 0.005 | 0.5 | 0.02 | NEMSOK - Kód prvku: TI05.04.1001; Požární odolnost: E; Systém kotvení: Lepený + přitížený; Součinitel prostupu tepla: 0.022; Součinitel difúzního odporu: 100 - 250; Způsob spojení vrstev: Lepený
 | Půdorys 2.NP | FLOOR | SPÁDOVÉ KLÍNY PIR 3% | yes | Spádové klíny (Atribut objektu!) | Izolace tepelné | SPÁDOVÉ KLÍNY PIR 3% | 1564Des0000001993 | m3 | Deska | NEW | no | 0.25 | 0.5 | 0.25 | 0.005 | 2 | 0.005 | 0.5 | 0.02 | NEMSOK - Kód prvku: TI05.04.1001; Požární odolnost: E; Systém kotvení: Lepený + přitížený; Součinitel prostupu tepla: 0.022; Součinitel difúzního odporu: 100 - 250; Způsob spojení vrstev: Lepený
 | Půdorys 2.NP | FLOOR | SPÁDOVÉ KLÍNY PIR 3% | yes | Spádové klíny (Atribut objektu!) | Izolace tepelné | SPÁDOVÉ KLÍNY PIR 3% | 1564Des0000003028 | m3 | Deska | NEW | no | 0.25 | 0.5 | 0.25 | 0.005 | 2 | 0.005 | 0.5 | 0.02 | NEMSOK - Kód prvku: TI05.04.1002; Požární odolnost: E; Systém kotvení: Lepený + přitížený; Součinitel prostupu tepla: 0.022; Součinitel difúzního odporu: 100 - 250; Způsob spojení vrstev: Lepený
 | Půdorys 2.NP | FLOOR | SPÁDOVÉ KLÍNY PIR 3% | yes | Spádové klíny (Atribut objektu!) | Izolace tepelné | SPÁDOVÉ KLÍNY PIR 3% | 1564Des0000003025 | m3 | Deska | NEW | no | 0.25 | 0.5 | 0.25 | 0.005 | 2 | 0.005 | 0.5 | 0.02 | NEMSOK - Kód prvku: TI05.04.1002; Požární odolnost: E; Systém kotvení: Lepený + přitížený; Součinitel prostupu tepla: 0.022; Součinitel difúzního odporu: 100 - 250; Způsob spojení vrstev: Lepený
 | Půdorys 2.NP | FLOOR | SPÁDOVÉ KLÍNY PIR 3% | yes | Spádové klíny (Atribut objektu!) | Izolace tepelné | SPÁDOVÉ KLÍNY PIR 3% | 1564Des0798453433 | m3 | Deska | NEW | no | 0.25 | 0.5 | 0.25 | 0.005 | 2 | 0.005 | 0.5 | 0.02 | NEMSOK - Kód prvku: TI05.04.1003; Požární odolnost: E; Systém kotvení: Lepený + přitížený; Součinitel prostupu tepla: 0.022; Součinitel difúzního odporu: 100 - 250; Způsob spojení vrstev: Lepený
 | Půdorys 2.NP | FLOOR | SPÁDOVÉ KLÍNY PIR 3% | yes | Spádové klíny (Atribut objektu!) | Izolace tepelné | SPÁDOVÉ KLÍNY PIR 3% | 1564Des0798453436 | m3 | Deska | NEW | no | 0.25 | 0.5 | 0.25 | 0.005 | 2 | 0.005 | 0.5 | 0.02 | NEMSOK - Kód prvku: TI05.04.1003; Požární odolnost: E; Systém kotvení: Lepený + přitížený; Součinitel prostupu tepla: 0.022; Součinitel difúzního odporu: 100 - 250; Způsob spojení vrstev: Lepený
 | Půdorys 2.NP | FLOOR | SPÁDOVÉ KLÍNY PIR 3% | yes | Spádové klíny (Atribut objektu!) | Izolace tepelné | SPÁDOVÉ KLÍNY PIR 3% | 1564Des0798453439 | m3 | Deska | NEW | no | 0.25 | 0.5 | 0.25 | 0.005 | 2 | 0.005 | 0.5 | 0.02 | NEMSOK - Kód prvku: TI05.04.1003; Požární odolnost: E; Systém kotvení: Lepený + přitížený; Součinitel prostupu tepla: 0.022; Součinitel difúzního odporu: 100 - 250; Způsob spojení vrstev: Lepený
 | Půdorys 2.NP | FLOOR | SPÁDOVÉ KLÍNY PIR 3% | yes | Spádové klíny (Atribut objektu!) | Izolace tepelné | SPÁDOVÉ KLÍNY PIR 3% | 1564Des0798479362 | m3 | Deska | NEW | no | 0.25 | 0.5 | 0.25 | 0.005 | 2 | 0.005 | 0.5 | 0.02 | NEMSOK - Kód prvku: TI05.04.1001; Požární odolnost: E; Systém kotvení: Lepený + přitížený; Součinitel prostupu tepla: 0.022; Součinitel difúzního odporu: 100 - 250; Způsob spojení vrstev: Lepený
 | Půdorys 2.NP | FLOOR | MINERÁLNÍ VATA | yes | Izolace střechy (Atribut objektu!) | Izolace tepelné | MINERÁLNÍ VATA | 1564Des0798472218 | m3 | Deska | NEW | no | 10.97 | 5.58 | 10.969 | 1.097 | 109.7 | 1.097 | 1.966 | 0.1 | NEMSOK - Kód prvku: TI06.04.2001; Požární odolnost: A1; Systém kotvení: Lepený; Součinitel prostupu tepla: 0.036; Součinitel difúzního odporu: 1; Způsob spojení vrstev: Lepený + mechanicky kotvený
 | Půdorys 2.NP | FLOOR | MINERÁLNÍ VATA | yes | Izolace střechy (Atribut objektu!) | Izolace tepelné | MINERÁLNÍ VATA | 1564Des0798472460 | m3 | Deska | NEW | no | 8.912 | 0.25 | 8.915 | 0.891 | 71.8 | 0.891 | 35.65 | 0.1 | NEMSOK - Kód prvku: TI06.04.2003; Požární odolnost: A1; Systém kotvení: Lepený; Součinitel prostupu tepla: 0.036; Součinitel difúzního odporu: 1; Způsob spojení vrstev: Lepený + mechanicky kotvený
 | Půdorys 2.NP | FLOOR | SPÁDOVÉ KLÍNY PIR 3% | yes | Spádové klíny (Atribut objektu!) | Izolace tepelné | SPÁDOVÉ KLÍNY PIR 3% | 1564Des0000001811 | m3 | Deska | NEW | no | 92.287 | 6.128 | 92.026 | 14.584 | 58.77 | 14.53 | 15.06 | 0.158 | NEMSOK - Kód prvku: TI05.04.1001; Požární odolnost: E; Systém kotvení: Lepený + přitížený; Součinitel prostupu tepla: 0.022; Součinitel difúzního odporu: 100 - 250; Způsob spojení vrstev: Lepený
 | Půdorys 2.NP | FLOOR | SPÁDOVÉ KLÍNY PIR 3% | yes | Spádové klíny (Atribut objektu!) | Izolace tepelné | SPÁDOVÉ KLÍNY PIR 3% | 1564Des0000002998 | m3 | Deska | NEW | no | 61.034 | 5.559 | 61.061 | 4.636 | 39.02 | 4.636 | 10.98 | 0.076 | NEMSOK - Kód prvku: TI05.04.1002; Požární odolnost: E; Systém kotvení: Lepený + přitížený; Součinitel prostupu tepla: 0.022; Součinitel difúzního odporu: 100 - 250; Způsob spojení vrstev: Lepený
 | Půdorys 2.NP | FLOOR | SPÁDOVÉ KLÍNY PIR 3% | yes | Spádové klíny (Atribut objektu!) | Izolace tepelné | SPÁDOVÉ KLÍNY PIR 3% | 1564Des0798453442 | m3 | Deska | NEW | no | 582.374 | 13.394 | 580.541 | 92.405 | 139.66 | 92.154 | 43.48 | 0.159 | NEMSOK - Kód prvku: TI05.04.1003; Požární odolnost: E; Systém kotvení: Lepený + přitížený; Součinitel prostupu tepla: 0.022; Součinitel difúzního odporu: 100 - 250; Způsob spojení vrstev: Lepený
 | Půdorys 2.NP | FLOOR | MINERÁLNÍ VATA | yes | Izolace střechy (Atribut objektu!) | Izolace tepelné | MINERÁLNÍ VATA | 1564Des0798472335 | m3 | Deska | NEW | no | 23.653 | 2.67 | 23.656 | 2.365 | 189.72 | 2.365 | 8.859 | 0.1 | NEMSOK - Kód prvku: TI06.04.2002; Požární odolnost: A1; Součinitel prostupu tepla: 0.036; Součinitel difúzního odporu: 1; Způsob spojení vrstev: Lepený + mechanicky kotvený
 | Půdorys 2.NP | FLOOR | PIR | yes | Izolace střechy (Atribut objektu!) | Izolace tepelné | PIR | 1566Des0000000168 | m3 | Deska | NEW | no | 5.184 | 1.92 | 5.184 | 1.348 | 9.24 | 1.348 | 2.7 | 0.26 | NEMSOK - Kód prvku: TI05.04.1001; Systém kotvení: Lepený + mechanicky kotvený; Součinitel prostupu tepla: 0.022; Součinitel difúzního odporu: 150
 | Půdorys 2.NP | FLOOR | ZELEZOBETONOVÁ KCE | yes | Betonová deska (Atribut objektu!) | Betonářské práce | ZELEZOBETONOVÁ KCE | 1566Des0000000165 | m3 | Deska | NEW | no | 3.36 | 2.1 | 3.36 | 0.84 | 7.4 | 0.84 | 1.6 | 0.25 | NEMSOK - Kód prvku: SK01.04.0001; Stupeň vyztužení: 0; Podlaží: 1.NP; Požární odolnost: A
 | Půdorys 2.NP | FLOOR | PIR | yes | Izolace střechy (Atribut objektu!) | Izolace tepelné | PIR | 1566Des0000000204 | m3 | Deska | NEW | no | 358.145 | 0.8 | 358.145 | 93.118 | 92.9 | 93.118 | 447.681 | 0.26 | NEMSOK - Kód prvku: TI05.04.1002; Požární odolnost: E; Systém kotvení: Mechanicky kotvený + přitížený; Součinitel prostupu tepla: 0.022; Součinitel difúzního odporu: 150; Způsob spojení vrstev: Lepený + mechanicky kotvený
 | Půdorys 3.NP | FLOOR | VĚNEC | yes | Betonová deska (Atribut objektu!) | Betonářské práce | VĚNEC | 1654Des0000000480 | m3 | Deska | EXISTING | yes | 7.597 | 1.07 | 7.597 | 1.899 | 16.34 | 1.899 | 7.1 | 0.25
 | Půdorys 3.NP | FLOOR | PZD | yes | Betonová deska (Atribut objektu!) | Betonářské práce | PZD | 1654Des0000000485 | m3 | Deska | EXISTING | yes | 31.746 | 2.2 | 31.646 | 7.937 | 33.26 | 7.912 | 14.43 | 0.25
 | Půdorys 3.NP | FLOOR | RZT | yes | Betonová deska (Atribut objektu!) | Betonářské práce | RZT | 1654Des0000000487 | m3 | Deska | EXISTING | yes | 8.4 | 6 | 8.4 | 2.1 | 14.8 | 2.1 | 1.4 | 0.25
 | Půdorys 3.NP | FLOOR | DZH | yes | Betonová deska (Atribut objektu!) | Betonářské práce | DZH | 1654Des0000000491 | m3 | Deska | EXISTING | yes | 5.44 | 3.4 | 5.44 | 1.36 | 10 | 1.36 | 1.6 | 0.25
 | Půdorys 3.NP | FLOOR | PZD | yes | Betonová deska (Atribut objektu!) | Betonářské práce | PZD | 1654Des0000000493 | m3 | Deska | EXISTING | yes | 12.98 | 5.9 | 12.98 | 3.245 | 16.2 | 3.245 | 2.2 | 0.25
 | Půdorys 3.NP | FLOOR | RZT | yes | Betonová deska (Atribut objektu!) | Betonářské práce | RZT | 1654Des0000000495 | m3 | Deska | EXISTING | yes | 8.26 | 5.9 | 8.26 | 2.065 | 14.6 | 2.065 | 1.4 | 0.25
 | Půdorys 3.NP | FLOOR | RZT | yes | Betonová deska (Atribut objektu!) | Betonářské práce | RZT | 1654Des0000000514 | m3 | Deska | EXISTING | yes | 35.28 | 25.2 | 35.28 | 8.82 | 53.2 | 8.82 | 1.4 | 0.25
 | Půdorys 3.NP | FLOOR | RZT | yes | Betonová deska (Atribut objektu!) | Betonářské práce | RZT | 1654Des0000000519 | m3 | Deska | EXISTING | yes | 8.4 | 6 | 8.4 | 2.1 | 14.8 | 2.1 | 1.4 | 0.25
 | Půdorys 3.NP | FLOOR | PZD | yes | Betonová deska (Atribut objektu!) | Betonářské práce | PZD | 1654Des0000000529 | m3 | Deska | EXISTING | yes | 99.12 | 25.2 | 97.46 | 24.78 | 89.2 | 24.365 | 3.933 | 0.25
 | Půdorys 3.NP | FLOOR | RZT | yes | Betonová deska (Atribut objektu!) | Betonářské práce | RZT | 1654Des0000000543 | m3 | Deska | EXISTING | yes | 16.8 | 12 | 16.8 | 4.2 | 26.8 | 4.2 | 1.4 | 0.25
 | Půdorys 3.NP | FLOOR | PZD | yes | Betonová deska (Atribut objektu!) | Betonářské práce | PZD | 1654Des0000000583 | m3 | Deska | EXISTING | yes | 5.52 | 4.6 | 5.52 | 1.38 | 11.6 | 1.38 | 1.2 | 0.25
 | Půdorys 3.NP | FLOOR | PZD | yes | Betonová deska (Atribut objektu!) | Betonářské práce | PZD | 1654Des0000000587 | m3 | Deska | EXISTING | yes | 5.52 | 4.6 | 5.52 | 1.38 | 11.6 | 1.38 | 1.2 | 0.25
 | Půdorys 3.NP | FLOOR | PZD | yes | Betonová deska (Atribut objektu!) | Betonářské práce | PZD | 1654Des0000000593 | m3 | Deska | EXISTING | yes | 2.64 | 2.2 | 2.64 | 0.66 | 6.8 | 0.66 | 1.2 | 0.25
 | Půdorys 3.NP | FLOOR | RZT | yes | Betonová deska (Atribut objektu!) | Betonářské práce | RZT | 1654Des0000000595 | m3 | Deska | EXISTING | yes | 37.1 | 26.5 | 37.1 | 9.275 | 55.8 | 9.275 | 1.4 | 0.25
 | Půdorys 3.NP | FLOOR | RZT | yes | Betonová deska (Atribut objektu!) | Betonářské práce | RZT | 1654Des0000000601 | m3 | Deska | EXISTING | yes | 37.1 | 26.5 | 37.1 | 9.275 | 55.8 | 9.275 | 1.4 | 0.25
 | Půdorys 3.NP | FLOOR | PZD | yes | Betonová deska (Atribut objektu!) | Betonářské práce | PZD | 1654Des0000000541 | m3 | Deska | EXISTING | yes | 99.12 | 25.2 | 97.984 | 24.78 | 86.4 | 24.496 | 3.933 | 0.25
 | Půdorys 3.NP | FLOOR | PZD | yes | Betonová deska (Atribut objektu!) | Betonářské práce | PZD | 1654Des0000000497 | m3 | Deska | EXISTING | yes | 9.345 | 2.67 | 9.345 | 2.336 | 12.34 | 2.336 | 3.5 | 0.25
 | Půdorys 3.NP | FLOOR | RZT | yes | Betonová deska (Atribut objektu!) | Betonářské práce | RZT | 1654Des0000000482 | m3 | Deska | EXISTING | yes | 20.202 | 14.43 | 20.202 | 5.051 | 31.66 | 5.051 | 1.4 | 0.25
 | Půdorys 3.NP | FLOOR | RZT | yes | Betonová deska (Atribut objektu!) | Betonářské práce | RZT | 1654Des0000000597 | m3 | Deska | EXISTING | yes | 37.1 | 26.5 | 37.1 | 9.275 | 55.8 | 9.275 | 1.4 | 0.25
 | Půdorys 3.NP | FLOOR | RZT | yes | Betonová deska (Atribut objektu!) | Betonářské práce | RZT | 1654Des0000000599 | m3 | Deska | EXISTING | yes | 37.1 | 26.5 | 37.1 | 9.275 | 55.8 | 9.275 | 1.4 | 0.25
 | Půdorys 3.NP | FLOOR | PZD | yes | Betonová deska (Atribut objektu!) | Betonářské práce | PZD | 1654Des0000000332 | m3 | Deska | EXISTING | yes | 7.75 | 3.1 | 7.75 | 1.55 | 11.2 | 1.55 | 2.5 | 0.2
 | Půdorys 3.NP | FLOOR | ZELEZOBETONOVÁ KCE | yes | Betonová deska (Atribut objektu!) | Betonářské práce | ZELEZOBETONOVÁ KCE | 1654Des0000000329 | m3 | Deska | EXISTING | yes | 6.3 | 3 | 6.29 | 1.26 | 10.2 | 1.258 | 2.1 | 0.2
 | Půdorys 3.NP | FLOOR | ZELEZOBETONOVÁ KCE | yes | Betonová deska (Atribut objektu!) | Betonářské práce | ZELEZOBETONOVÁ KCE | 1654Des0000000326 | m3 | Deska | EXISTING | yes | 20.04 | 2.4 | 19.97 | 4.008 | 21.5 | 3.994 | 8.35 | 0.2
 | Půdorys 3.NP | FLOOR | PZD | yes | Betonová deska (Atribut objektu!) | Betonářské práce | PZD | 1654Des0000000561 | m3 | Deska | EXISTING | yes | 103.6 | 25.2 | 99.01 | 25.9 | 82.8 | 24.752 | 4.111 | 0.25
 | Půdorys 3.NP | FLOOR | RZT | yes | Betonová deska (Atribut objektu!) | Betonářské práce | RZT | 1654Des0000000565 | m3 | Deska | EXISTING | yes | 8.68 | 6.2 | 8.68 | 2.17 | 15.2 | 2.17 | 1.4 | 0.25
 | Půdorys 3.NP | FLOOR | RZT | yes | Betonová deska (Atribut objektu!) | Betonářské práce | RZT | 1654Des0000000563 | m3 | Deska | EXISTING | yes | 3.64 | 2.6 | 3.64 | 0.91 | 8 | 0.91 | 1.4 | 0.25
 | Půdorys 3.NP | FLOOR | PZD | yes | Betonová deska (Atribut objektu!) | Betonářské práce | PZD | 1654Des0000000574 | m3 | Deska | EXISTING | yes | 55.44 | 25.2 | 54.69 | 13.86 | 54.8 | 13.672 | 2.2 | 0.25
 | Půdorys 3.NP | FLOOR | PZD | yes | Betonová deska (Atribut objektu!) | Betonářské práce | PZD | 1654Des0000000510 | m3 | Deska | EXISTING | yes | 55.44 | 2.2 | 54.99 | 13.86 | 54.8 | 13.748 | 25.2 | 0.25
 | Půdorys 3.NP | FLOOR | PZD | yes | Betonová deska (Atribut objektu!) | Betonářské práce | PZD | 1654Des0000000500 | m3 | Deska | EXISTING | yes | 62.775 | 1.35 | 61.965 | 15.694 | 44.1 | 15.491 | 46.5 | 0.25
 | Půdorys 3.NP | FLOOR | RZT | yes | Betonová deska (Atribut objektu!) | Betonářské práce | RZT | 1654Des0000000512 | m3 | Deska | EXISTING | yes | 35.28 | 25.2 | 35.28 | 8.82 | 53.2 | 8.82 | 1.4 | 0.25
11 x  | Půdorys 3.NP | ROOF | ASFALTOVÁ HYDROIZOLACE 0.01 m, KAČÍREK 0.06 m
 | Půdorys 3.NP | FLOOR | SPÁDOVÉ KLÍNY PIR 3% | yes | Spádové klíny (Atribut objektu!) | Izolace tepelné | SPÁDOVÉ KLÍNY PIR 3% | 1664Des0000000959 | m3 | Deska | NEW | no | 342.403 | 13.735 | 342.556 | 50.603 | 98.48 | 50.603 | 24.93 | 0.148 | NEMSOK - Kód prvku: TI05.05.2001; Požární odolnost: E; Systém kotvení: Lepený + přitížený; Součinitel prostupu tepla: 0.022; Součinitel difúzního odporu: 150; Způsob spojení vrstev: Lepený
 | Půdorys 3.NP | FLOOR | SPÁDOVÉ KLÍNY PIR 3% | yes | Spádové klíny (Atribut objektu!) | Izolace tepelné | SPÁDOVÉ KLÍNY PIR 3% | 1664Des0000000011 | m3 | Deska | NEW | no | 5.184 | 2.7 | 5.186 | 0.253 | 9.24 | 0.253 | 1.92 | 0.049 | NEMSOK - Kód prvku: TI05.05.2002; Požární odolnost: E; Systém kotvení: Lepený + přitížený; Součinitel prostupu tepla: 0.022; Součinitel difúzního odporu: 150; Způsob spojení vrstev: Lepený
 | Půdorys 3.NP | FLOOR | MINERÁLNÍ VATA | yes |  | Zateplovací systémy | MINERÁLNÍ VATA | 1664Des0000000730 | m3 | Stěna | NEW | no | 19.16 | 0.751 | 19.16 | 1.916 | 131.88 | 1.916 | 25.5 | 0.1 | NEMSOK - Kód prvku: TI06.05.1001; Požární odolnost: A1; Součinitel prostupu tepla: 0.036; Součinitel difúzního odporu: 1; Způsob spojení vrstev: Lepený + mechanicky kotvený
 | Půdorys 3.NP | FLOOR | MINERÁLNÍ VATA | yes | Izolace střechy (Atribut objektu!) | Izolace tepelné | MINERÁLNÍ VATA | 1664Des0000000843 | m3 | Deska | NEW | no | 0.36 | 0.6 | 0.36 | 0.036 | 2.4 | 0.036 | 0.6 | 0.1 | NEMSOK - Kód prvku: TI06.05.2001; Požární odolnost: A1; Součinitel prostupu tepla: 0.036; Součinitel difúzního odporu: 1; Způsob spojení vrstev: Lepený
 | Půdorys 3.NP | FLOOR | MINERÁLNÍ VATA | yes | Izolace střechy (Atribut objektu!) | Izolace tepelné | MINERÁLNÍ VATA | 1664Des0000000857 | m3 | Deska | NEW | no | 0.72 | 0.6 | 0.72 | 0.072 | 3.6 | 0.072 | 1.2 | 0.1 | NEMSOK - Kód prvku: TI06.05.2001; Požární odolnost: A1; Součinitel prostupu tepla: 0.036; Součinitel difúzního odporu: 1; Způsob spojení vrstev: Lepený
 | Půdorys 3.NP | FLOOR | MINERÁLNÍ VATA | yes | Izolace střechy (Atribut objektu!) | Izolace tepelné | MINERÁLNÍ VATA | 1664Des0000000849 | m3 | Deska | NEW | no | 0.945 | 1.05 | 0.945 | 0.095 | 3.9 | 0.095 | 0.9 | 0.1 | NEMSOK - Kód prvku: TI06.05.2001; Požární odolnost: A1; Součinitel prostupu tepla: 0.036; Součinitel difúzního odporu: 1; Způsob spojení vrstev: Lepený
 | Půdorys 3.NP | FLOOR | MINERÁLNÍ VATA | yes | Izolace střechy (Atribut objektu!) | Izolace tepelné | MINERÁLNÍ VATA | 1664Des0000000846 | m3 | Deska | NEW | no | 0.36 | 0.6 | 0.36 | 0.036 | 2.4 | 0.036 | 0.6 | 0.1 | NEMSOK - Kód prvku: TI06.05.2001; Požární odolnost: A1; Součinitel prostupu tepla: 0.036; Součinitel difúzního odporu: 1; Způsob spojení vrstev: Lepený
 | Půdorys 3.NP | FLOOR | MINERÁLNÍ VATA | yes | Izolace střechy (Atribut objektu!) | Izolace tepelné | MINERÁLNÍ VATA | 1664Des0000000852 | m3 | Deska | NEW | no | 0.36 | 0.6 | 0.36 | 0.036 | 2.4 | 0.036 | 0.6 | 0.1 | NEMSOK - Kód prvku: TI06.05.2001; Požární odolnost: A1; Součinitel prostupu tepla: 0.036; Součinitel difúzního odporu: 1; Způsob spojení vrstev: Lepený
 | Půdorys 3.NP | ROOF | ASFALTOVÁ HYDROIZOLACE 0.01 m, I.S4 - KAČÍREK 0.01 m
 | Půdorys 4.NP | FLOOR | PZD | yes | Betonová deska (Atribut objektu!) | Betonářské práce | PZD | 1754Des0000000974 | m3 | Deska | EXISTING | yes | 115.92 | 25.2 | 115.57 | 28.98 | 59.6 | 28.892 | 4.6 | 0.25
 | Půdorys 4.NP | FLOOR | PZD | yes | Betonová deska (Atribut objektu!) | Betonářské práce | PZD | 1754Des0000000903 | m3 | Deska | EXISTING | yes | 31.746 | 2.2 | 31.706 | 7.937 | 33.26 | 7.927 | 14.43 | 0.25
 | Půdorys 4.NP | FLOOR | PZD | yes | Betonová deska (Atribut objektu!) | Betonářské práce | PZD | 1754Des0000000950 | m3 | Deska | EXISTING | yes | 2.64 | 2.2 | 2.64 | 0.66 | 6.8 | 0.66 | 1.2 | 0.25
 | Půdorys 4.NP | FLOOR | PZD | yes | Betonová deska (Atribut objektu!) | Betonářské práce | PZD | 1754Des0000000944 | m3 | Deska | EXISTING | yes | 5.52 | 4.6 | 5.52 | 1.38 | 11.6 | 1.38 | 1.2 | 0.25
 | Půdorys 4.NP | FLOOR | RZT | yes | Betonová deska (Atribut objektu!) | Betonářské práce | RZT | 1754Des0000000952 | m3 | Deska | EXISTING | yes | 37.1 | 26.5 | 37.1 | 9.275 | 55.8 | 9.275 | 1.4 | 0.25
 | Půdorys 4.NP | FLOOR | RZT | yes | Betonová deska (Atribut objektu!) | Betonářské práce | RZT | 1754Des0000000932 | m3 | Deska | EXISTING | yes | 3.64 | 2.6 | 3.64 | 0.91 | 8 | 0.91 | 1.4 | 0.25
 | Půdorys 4.NP | FLOOR | RZT | yes | Betonová deska (Atribut objektu!) | Betonářské práce | RZT | 1754Des0000000956 | m3 | Deska | EXISTING | yes | 37.1 | 26.5 | 37.1 | 9.275 | 55.8 | 9.275 | 1.4 | 0.25
 | Půdorys 4.NP | FLOOR | RZT | yes | Betonová deska (Atribut objektu!) | Betonářské práce | RZT | 1754Des0000000934 | m3 | Deska | EXISTING | yes | 8.68 | 6.2 | 8.68 | 2.17 | 15.2 | 2.17 | 1.4 | 0.25
 | Půdorys 4.NP | FLOOR | RZT | yes | Betonová deska (Atribut objektu!) | Betonářské práce | RZT | 1754Des0000000958 | m3 | Deska | EXISTING | yes | 37.1 | 26.5 | 37.1 | 9.275 | 55.8 | 9.275 | 1.4 | 0.25
 | Půdorys 4.NP | FLOOR | RZT | yes | Betonová deska (Atribut objektu!) | Betonářské práce | RZT | 1754Des0000000905 | m3 | Deska | EXISTING | yes | 8.4 | 6 | 8.4 | 2.1 | 14.8 | 2.1 | 1.4 | 0.25
 | Půdorys 4.NP | FLOOR | RZT | yes | Betonová deska (Atribut objektu!) | Betonářské práce | RZT | 1754Des0000000915 | m3 | Deska | EXISTING | yes | 8.4 | 6 | 8.4 | 2.1 | 14.8 | 2.1 | 1.4 | 0.25
 | Půdorys 4.NP | FLOOR | PZD | yes | Betonová deska (Atribut objektu!) | Betonářské práce | PZD | 1754Des0000000940 | m3 | Deska | EXISTING | yes | 5.52 | 4.6 | 5.52 | 1.38 | 11.6 | 1.38 | 1.2 | 0.25
 | Půdorys 4.NP | FLOOR | DZH | yes | Betonová deska (Atribut objektu!) | Betonářské práce | DZH | 1754Des0000000907 | m3 | Deska | EXISTING | yes | 5.44 | 3.4 | 5.44 | 1.36 | 10 | 1.36 | 1.6 | 0.25
 | Půdorys 4.NP | FLOOR | PZD | yes | Betonová deska (Atribut objektu!) | Betonářské práce | PZD | 1754Des0000000909 | m3 | Deska | EXISTING | yes | 12.98 | 5.9 | 12.98 | 3.245 | 16.2 | 3.245 | 2.2 | 0.25
 | Půdorys 4.NP | FLOOR | RZT | yes | Betonová deska (Atribut objektu!) | Betonářské práce | RZT | 1754Des0000000911 | m3 | Deska | EXISTING | yes | 8.26 | 5.9 | 8.26 | 2.065 | 14.6 | 2.065 | 1.4 | 0.25
 | Půdorys 4.NP | FLOOR | ZELEZOBETONOVÁ KCE | yes | Betonová deska (Atribut objektu!) | Betonářské práce | ZELEZOBETONOVÁ KCE | 1754Des0000001749 | m3 | Deska | EXISTING | no | 40.85 | 4.3 | 40.85 | 6.127 | 27.6 | 6.127 | 9.5 | 0.15
 | Půdorys 4.NP | FLOOR | RZT | yes | Betonová deska (Atribut objektu!) | Betonářské práce | RZT | 1754Des0000000979 | m3 | Deska | EXISTING | yes | 20.202 | 14.43 | 20.202 | 5.051 | 31.66 | 5.051 | 1.4 | 0.25
 | Půdorys 4.NP | FLOOR | VĚNEC | yes | Betonová deska (Atribut objektu!) | Betonářské práce | VĚNEC | 1754Des0000000900 | m3 | Deska | EXISTING | yes | 7.597 | 1.07 | 7.597 | 1.899 | 16.34 | 1.899 | 7.1 | 0.25
 | Půdorys 4.NP | FLOOR | RZT | yes | Betonová deska (Atribut objektu!) | Betonářské práce | RZT | 1754Des0000002036 | m3 | Deska | EXISTING | yes | 21.84 | 1.4 | 21.84 | 5.46 | 34 | 5.46 | 15.6 | 0.25
 | Půdorys 4.NP | FLOOR | ZELEZOBETONOVÁ KCE | yes | Betonová deska (Atribut objektu!) | Betonářské práce | ZELEZOBETONOVÁ KCE | 1754Des0000000262 | m3 | Deska | EXISTING | yes | 8.5 | 3.4 | 8.5 | 2.125 | 11.8 | 2.027 | 2.5 | 0.25
 | Půdorys 4.NP | FLOOR | PZD | yes | Betonová deska (Atribut objektu!) | Betonářské práce | PZD | 1754Des0000000037 | m3 | Deska | EXISTING | yes | 22.545 | 2.7 | 22.545 | 2.254 | 22.1 | 2.254 | 8.35 | 0.1
 | Půdorys 4.NP | FLOOR | PZD | yes | Betonová deska (Atribut objektu!) | Betonářské práce | PZD | 1754Des0000000630 | m3 | Deska | EXISTING | yes | 7.2 | 2.4 | 7.19 | 0.72 | 10.8 | 0.719 | 3 | 0.1
 | Půdorys 4.NP | FLOOR | ZELEZOBETONOVÁ KCE | yes | Betonová deska (Atribut objektu!) | Betonářské práce | ZELEZOBETONOVÁ KCE | 1754Des0000002250 | m3 | Deska | EXISTING | yes | 3.703 | 1.21 | 3.703 | 0.741 | 8.54 | 0.741 | 3.06 | 0.2
 | Půdorys 4.NP | FLOOR | PZD | yes | Betonová deska (Atribut objektu!) | Betonářské práce | PZD | 1754Des0000000930 | m3 | Deska | EXISTING | yes | 103.6 | 25.2 | 98.885 | 25.9 | 82.8 | 24.721 | 4.111 | 0.25
 | Půdorys 4.NP | FLOOR | PZD | yes | Betonová deska (Atribut objektu!) | Betonářské práce | PZD | 1754Des0000000938 | m3 | Deska | EXISTING | yes | 55.44 | 25.2 | 54.872 | 13.86 | 54.8 | 13.718 | 2.2 | 0.25
 | Půdorys 4.NP | FLOOR | PZD | yes | Betonová deska (Atribut objektu!) | Betonářské práce | PZD | 1754Des0000000893 | m3 | Deska | EXISTING | yes | 55.44 | 2.2 | 55.36 | 13.86 | 54.8 | 13.84 | 25.2 | 0.25
 | Půdorys 4.NP | FLOOR | RZT | yes | Betonová deska (Atribut objektu!) | Betonářské práce | RZT | 1754Des0000000913 | m3 | Deska | EXISTING | yes | 35.28 | 25.2 | 35.245 | 8.82 | 53.2 | 8.811 | 1.4 | 0.25
 | Půdorys 4.NP | FLOOR | RZT | yes | Betonová deska (Atribut objektu!) | Betonářské práce | RZT | 1754Des0000000954 | m3 | Deska | EXISTING | yes | 37.1 | 26.5 | 37.065 | 9.275 | 55.8 | 9.266 | 1.4 | 0.25
 | Půdorys 4.NP | FLOOR | RZT | yes | Betonová deska (Atribut objektu!) | Betonářské práce | RZT | 1754Des0000000895 | m3 | Deska | EXISTING | yes | 35.28 | 25.2 | 35.28 | 8.82 | 53.2 | 8.82 | 1.4 | 0.25
 | Půdorys 4.NP | FLOOR | PZD | yes | Betonová deska (Atribut objektu!) | Betonářské práce | PZD | 1754Des0000001981 | m3 | Deska | EXISTING | yes | 6.6 | 2.2 | 6.6 | 1.65 | 10.4 | 1.65 | 3 | 0.25
 | Půdorys 4.NP | FLOOR | PZD | yes | Betonová deska (Atribut objektu!) | Betonářské práce | PZD | 1754Des0000002070 | m3 | Deska | EXISTING | yes | 10.8 | 3.6 | 11.819 | 2.7 | 13.2 | 2.7 | 3 | 0.25
 | Půdorys 4.NP | FLOOR | PZD | yes | Betonová deska (Atribut objektu!) | Betonářské práce | PZD | 1754Des0000000921 | m3 | Deska | EXISTING | yes | 99.12 | 25.2 | 98.59 | 24.78 | 89.2 | 24.647 | 3.933 | 0.25
 | Půdorys 4.NP | FLOOR | PZD | yes | Betonová deska (Atribut objektu!) | Betonářské práce | PZD | 1754Des0000000898 | m3 | Deska | EXISTING | yes | 41.52 | 3 | 41.25 | 10.38 | 42 | 10.313 | 13.84 | 0.25
 | Půdorys 4.NP | FLOOR | PIR | yes | Izolace střechy (Atribut objektu!) | Izolace tepelné | PIR | 1766Des0000000003 | m3 | Deska | NEW | no | 602.417 | 17.697 | 602.418 | 156.628 | 167.52 | 156.628 | 34.04 | 0.26 | NEMSOK - Kód prvku: TI05.05.1001; Požární odolnost: E; Systém kotvení: Mechanicky kotvený + přitížený; Součinitel prostupu tepla: 0.022; Součinitel difúzního odporu: 150; Způsob spojení vrstev: Lepený + mechanicky kotvený
 | Půdorys 4.NP | FLOOR | PIR | yes | Izolace střechy (Atribut objektu!) | Izolace tepelné | PIR | 1766Des0000000123 | m3 | Deska | NEW | no | 6.142 | 2.73 | 6.143 | 1.597 | 9.96 | 1.597 | 2.25 | 0.26 | NEMSOK - Kód prvku: TI05.05.1003; Požární odolnost: E; Systém kotvení: Mechanicky kotvený + přitížený; Součinitel prostupu tepla: 0.022; Součinitel difúzního odporu: 150; Způsob spojení vrstev: Lepený + mechanicky kotvený
 | Půdorys 4.NP | FLOOR | PIR | yes | Izolace střechy (Atribut objektu!) | Izolace tepelné | PIR | 1766Des0000000144 | m3 | Deska | NEW | no | 9.828 | 2.73 | 10.755 | 3.011 | 12.66 | 3.011 | 3.6 | 0.306 | NEMSOK - Kód prvku: TI05.05.1004; Požární odolnost: E; Systém kotvení: Mechanicky kotvený + přitížený; Součinitel prostupu tepla: 0.022; Součinitel difúzního odporu: 150; Způsob spojení vrstev: Lepený + mechanicky kotvený
 | Půdorys 4.NP | FLOOR | PIR | yes | Izolace střechy (Atribut objektu!) | Izolace tepelné | PIR | 1766Des0000000120 | m3 | Deska | NEW | no | 5.058 | 2.73 | 5.058 | 1.315 | 11.16 | 1.315 | 1.853 | 0.26 | NEMSOK - Kód prvku: TI05.05.1002; Požární odolnost: E; Systém kotvení: Mechanicky kotvený + přitížený; Součinitel prostupu tepla: 0.022; Součinitel difúzního odporu: 150; Způsob spojení vrstev: Lepený + mechanicky kotvený
 | Půdorys 5.NP | FLOOR | RZT | yes | Betonová deska (Atribut objektu!) | Betonářské práce | RZT | 1854Des0000001232 | m3 | Deska | EXISTING | yes | 12.04 | 8.6 | 12.04 | 3.01 | 20 | 3.01 | 1.4 | 0.25
 | Půdorys 5.NP | FLOOR | PZD | yes | Betonová deska (Atribut objektu!) | Betonářské práce | PZD | 1854Des0000001247 | m3 | Deska | EXISTING | yes | 29.75 | 3.5 | 29.75 | 7.437 | 24 | 7.437 | 8.5 | 0.25
 | Půdorys 5.NP | FLOOR | DZH | yes | Betonová deska (Atribut objektu!) | Betonářské práce | DZH | 1854Des0000000924 | m3 | Deska | EXISTING | yes | 27.69 | 3.9 | 27.69 | 6.922 | 22 | 6.922 | 7.1 | 0.25
 | Půdorys 5.NP | FLOOR | VĚNEC | yes | Betonová deska (Atribut objektu!) | Betonářské práce | VĚNEC | 1854Des0000000941 | m3 | Deska | EXISTING | yes | 7.1 | 1 | 7.1 | 1.775 | 16.2 | 1.775 | 7.1 | 0.25
 | Půdorys 5.NP | FLOOR | PZD | yes | Betonová deska (Atribut objektu!) | Betonářské práce | PZD | 1854Des0000000881 | m3 | Deska | EXISTING | yes | 72.68 | 15.8 | 72.59 | 18.17 | 40.8 | 18.147 | 4.6 | 0.25
 | Půdorys 5.NP | FLOOR | PZD | yes | Betonová deska (Atribut objektu!) | Betonářské práce | PZD | 1854Des0000001254 | m3 | Deska | EXISTING | yes | 18.7 | 8.5 | 18.66 | 4.675 | 21.4 | 4.665 | 2.2 | 0.25
 | Půdorys 5.NP | FLOOR | RZT | yes | Betonová deska (Atribut objektu!) | Betonářské práce | RZT | 1854Des0000000867 | m3 | Deska | EXISTING | yes | 22.12 | 15.8 | 22.12 | 5.53 | 34.4 | 5.53 | 1.4 | 0.25
 | Půdorys 5.NP | FLOOR | PZD | yes | Betonová deska (Atribut objektu!) | Betonářské práce | PZD | 1854Des0000000865 | m3 | Deska | EXISTING | yes | 34.76 | 15.8 | 34.54 | 8.69 | 36 | 8.635 | 2.2 | 0.25
 | Půdorys 5.NP | FLOOR | RZT | yes | Betonová deska (Atribut objektu!) | Betonářské práce | RZT | 1854Des0000000889 | m3 | Deska | EXISTING | yes | 22.12 | 15.8 | 22.12 | 5.53 | 34.4 | 5.53 | 1.4 | 0.25
 | Půdorys 5.NP | FLOOR | ZELEZOBETONOVÁ KCE | yes | Betonová deska (Atribut objektu!) | Betonářské práce | ZELEZOBETONOVÁ KCE | 1854Des0000000309 | m3 | Deska | EXISTING | yes | 9.375 | 3.75 | 9.375 | 2.344 | 12.5 | 2.148 | 2.5 | 0.25
 | Půdorys 5.NP | FLOOR | ZELEZOBETONOVÁ KCE | yes | Betonová deska (Atribut objektu!) | Betonářské práce | ZELEZOBETONOVÁ KCE | 1854Des0000000291 | m3 | Deska | EXISTING | yes | 26.078 | 3.05 | 26.078 | 6.519 | 23.2 | 6.519 | 8.55 | 0.25
 | Půdorys 5.NP | FLOOR | ZELEZOBETONOVÁ KCE | yes | Betonová deska (Atribut objektu!) | Betonářské práce | ZELEZOBETONOVÁ KCE | 1854Des0000000304 | m3 | Deska | EXISTING | yes | 30.275 | 3.5 | 28.655 | 7.569 | 24.3 | 7.164 | 8.65 | 0.25
 | Půdorys 5.NP | FLOOR | RZT | yes | Betonová deska (Atribut objektu!) | Betonářské práce | RZT | 1854Des0000000885 | m3 | Deska | EXISTING | yes | 22.12 | 15.8 | 22.12 | 5.53 | 34.4 | 5.53 | 1.4 | 0.25
20 x  | Půdorys 5.NP | ROOF | ASFALTOVÁ HYDROIZOLACE 0.01 m, KAČÍREK 0.06 m
 | Půdorys 5.NP | ROOF | ASFALTOVÁ HYDROIZOLACE 0.01 m, KAČÍREK 0.04 m
 | Půdorys 5.NP | FLOOR | SPÁDOVÉ KLÍNY PIR 3% | yes | Spádové klíny (Atribut objektu!) | Izolace tepelné | SPÁDOVÉ KLÍNY PIR 3% | 1864Des0000000961 | m3 | Deska | NEW | no | 581.404 | 33.74 | 581.666 | 200.939 | 175.88 | 200.939 | 17.232 | 0.346 | NEMSOK - Kód prvku: TI05.06.2001; Požární odolnost: E; Systém kotvení: Lepený + přitížený; Součinitel prostupu tepla: 0.022; Součinitel difúzního odporu: 150; Způsob spojení vrstev: Lepený
 | Půdorys 5.NP | FLOOR | SPÁDOVÉ KLÍNY PIR 3% | yes | Spádové klíny (Atribut objektu!) | Izolace tepelné | SPÁDOVÉ KLÍNY PIR 3% | 1864Des0000000964 | m3 | Deska | NEW | no | 0.25 | 0.5 | 0.25 | 0.005 | 2 | 0.005 | 0.5 | 0.02 | NEMSOK - Kód prvku: TI05.06.2001; Požární odolnost: E; Systém kotvení: Lepený + přitížený; Součinitel prostupu tepla: 0.022; Součinitel difúzního odporu: 150; Způsob spojení vrstev: Lepený
 | Půdorys 5.NP | FLOOR | SPÁDOVÉ KLÍNY PIR 3% | yes | Spádové klíny (Atribut objektu!) | Izolace tepelné | SPÁDOVÉ KLÍNY PIR 3% | 1864Des0000000975 | m3 | Deska | NEW | no | 0.25 | 0.5 | 0.25 | 0.005 | 2 | 0.005 | 0.5 | 0.02 | NEMSOK - Kód prvku: TI05.06.2001; Požární odolnost: E; Systém kotvení: Lepený + přitížený; Součinitel prostupu tepla: 0.022; Součinitel difúzního odporu: 150; Způsob spojení vrstev: Lepený
 | Půdorys 5.NP | FLOOR | SPÁDOVÉ KLÍNY PIR 3% | yes | Spádové klíny (Atribut objektu!) | Izolace tepelné | SPÁDOVÉ KLÍNY PIR 3% | 1864Des0000000978 | m3 | Deska | NEW | no | 0.25 | 0.5 | 0.25 | 0.005 | 2 | 0.005 | 0.5 | 0.02 | NEMSOK - Kód prvku: TI05.06.2001; Požární odolnost: E; Systém kotvení: Lepený + přitížený; Součinitel prostupu tepla: 0.022; Součinitel difúzního odporu: 150; Způsob spojení vrstev: Lepený
 | Půdorys 5.NP | FLOOR | SPÁDOVÉ KLÍNY PIR 3% | yes | Spádové klíny (Atribut objektu!) | Izolace tepelné | SPÁDOVÉ KLÍNY PIR 3% | 1864Des0000000981 | m3 | Deska | NEW | no | 0.25 | 0.5 | 0.25 | 0.005 | 2 | 0.005 | 0.5 | 0.02 | NEMSOK - Kód prvku: TI05.06.2001; Požární odolnost: E; Systém kotvení: Lepený + přitížený; Součinitel prostupu tepla: 0.022; Součinitel difúzního odporu: 150; Způsob spojení vrstev: Lepený
 | Půdorys 5.NP | FLOOR | SPÁDOVÉ KLÍNY PIR 3% | yes | Spádové klíny (Atribut objektu!) | Izolace tepelné | SPÁDOVÉ KLÍNY PIR 3% | 1864Des0000004002 | m3 | Deska | NEW | no | 4.062 | 1.95 | 4.064 | 0.189 | 9.82 | 0.189 | 2.083 | 0.047 | NEMSOK - Kód prvku: TI05.06.2002; Požární odolnost: E; Systém kotvení: Lepený + přitížený; Součinitel prostupu tepla: 0.022; Součinitel difúzního odporu: 150; Způsob spojení vrstev: Lepený
 | Půdorys 5.NP | FLOOR | SPÁDOVÉ KLÍNY PIR 3% | yes | Spádové klíny (Atribut objektu!) | Izolace tepelné | SPÁDOVÉ KLÍNY PIR 3% | 1864Des0000004140 | m3 | Deska | NEW | no | 4.706 | 2.1 | 4.708 | 0.23 | 9.92 | 0.23 | 2.241 | 0.049 | NEMSOK - Kód prvku: TI05.06.2003; Požární odolnost: E; Systém kotvení: Lepený + přitížený; Součinitel prostupu tepla: 0.022; Součinitel difúzního odporu: 150; Způsob spojení vrstev: Lepený
 | Půdorys 5.NP | FLOOR | MINERÁLNÍ VATA | yes |  | Zateplovací systémy | MINERÁLNÍ VATA | 1864Des0000000904 | m3 | Stěna | NEW | no | 2.242 | 5.85 | 2.242 | 0.224 | 19.04 | 0.224 | 0.383 | 0.1 | NEMSOK - Kód prvku: TI06.06.1001; Požární odolnost: A1; Součinitel prostupu tepla: 0.036; Součinitel difúzního odporu: 1; Způsob spojení vrstev: Lepený + mechanicky kotvený
 | Půdorys 5.NP | FLOOR | MINERÁLNÍ VATA | yes | Izolace střechy (Atribut objektu!) | Izolace tepelné | MINERÁLNÍ VATA | 1864Des0000002766 | m3 | Deska | NEW | no | 1.02 | 0.85 | 1.02 | 0.102 | 4.1 | 0.102 | 1.2 | 0.1 | NEMSOK - Kód prvku: TI06.06.2001; Požární odolnost: A1; Součinitel prostupu tepla: 0.036; Součinitel difúzního odporu: 1; Způsob spojení vrstev: Lepený
 | Půdorys 5.NP | FLOOR | MINERÁLNÍ VATA | yes | Izolace střechy (Atribut objektu!) | Izolace tepelné | MINERÁLNÍ VATA | 1864Des0000002785 | m3 | Deska | NEW | no | 0.36 | 0.6 | 0.36 | 0.036 | 2.4 | 0.036 | 0.6 | 0.1 | NEMSOK - Kód prvku: TI06.06.2001; Požární odolnost: A1; Součinitel prostupu tepla: 0.036; Součinitel difúzního odporu: 1; Způsob spojení vrstev: Lepený
 | Půdorys 5.NP | FLOOR | MINERÁLNÍ VATA | yes | Izolace střechy (Atribut objektu!) | Izolace tepelné | MINERÁLNÍ VATA | 1864Des0000002794 | m3 | Deska | NEW | no | 0.36 | 0.6 | 0.36 | 0.036 | 2.4 | 0.036 | 0.6 | 0.1 | NEMSOK - Kód prvku: TI06.06.2001; Požární odolnost: A1; Součinitel prostupu tepla: 0.036; Součinitel difúzního odporu: 1; Způsob spojení vrstev: Lepený
 | Půdorys 5.NP | FLOOR | MINERÁLNÍ VATA | yes | Izolace střechy (Atribut objektu!) | Izolace tepelné | MINERÁLNÍ VATA | 1864Des0000002803 | m3 | Deska | NEW | no | 0.372 | 0.6 | 0.372 | 0.037 | 2.44 | 0.037 | 0.62 | 0.1 | NEMSOK - Kód prvku: TI06.06.2001; Požární odolnost: A1; Součinitel prostupu tepla: 0.036; Součinitel difúzního odporu: 1; Způsob spojení vrstev: Lepený
 | Půdorys 5.NP | FLOOR | MINERÁLNÍ VATA | yes | Izolace střechy (Atribut objektu!) | Izolace tepelné | MINERÁLNÍ VATA | 1864Des0000003862 | m3 | Deska | NEW | no | 0.27 | 0.6 | 0.27 | 0.027 | 2.1 | 0.027 | 0.45 | 0.1 | NEMSOK - Kód prvku: TI06.06.2001; Požární odolnost: A1; Součinitel prostupu tepla: 0.036; Součinitel difúzního odporu: 1; Způsob spojení vrstev: Lepený
 | Půdorys 5.NP | FLOOR | MINERÁLNÍ VATA | yes | Izolace střechy (Atribut objektu!) | Izolace tepelné | MINERÁLNÍ VATA | 1864Des0000009456 | m3 | Deska | NEW | no | 21.263 | 0.32 | 21.264 | 2.126 | 156.32 | 2.126 | 66.447 | 0.1 | NEMSOK - Kód prvku: TI06.06.2001; Požární odolnost: A1; Součinitel prostupu tepla: 0.036; Součinitel difúzního odporu: 1; Způsob spojení vrstev: Lepený + mechanicky kotvený
 | Půdorys 5.NP | FLOOR | MINERÁLNÍ VATA | yes |  | Zateplovací systémy | MINERÁLNÍ VATA | 1864Des0000000883 | m3 | Stěna | NEW | no | 6.426 | 0.364 | 6.426 | 0.643 | 41.6 | 0.643 | 17.64 | 0.1 | NEMSOK - Kód prvku: TI06.06.1001; Požární odolnost: A1; Součinitel prostupu tepla: 0.036; Součinitel difúzního odporu: 1; Způsob spojení vrstev: Lepený + mechanicky kotvený
 | Půdorys 5.NP | FLOOR | MINERÁLNÍ VATA | yes | Izolace střechy (Atribut objektu!) | Izolace tepelné | MINERÁLNÍ VATA | 1864Des0000005304 | m3 | Deska | NEW | no | 2.19 | 0.6 | 2.19 | 0.219 | 8.5 | 0.219 | 3.65 | 0.1 | NEMSOK - Kód prvku: TI06.06.2001; Požární odolnost: A1; Součinitel prostupu tepla: 0.036; Součinitel difúzního odporu: 1; Způsob spojení vrstev: Lepený
 | Půdorys 5.NP | FLOOR | MINERÁLNÍ VATA | yes |  | Zateplovací systémy | MINERÁLNÍ VATA | 1864Des0000000938 | m3 | Stěna | NEW | no | 3.861 | 3.08 | 3.861 | 0.386 | 22.76 | 0.386 | 1.253 | 0.1 | NEMSOK - Kód prvku: TI06.06.1001; Požární odolnost: A1; Součinitel prostupu tepla: 0.036; Součinitel difúzního odporu: 1; Způsob spojení vrstev: Lepený + mechanicky kotvený
 | Půdorys 5.NP | FLOOR | MINERÁLNÍ VATA | yes | Izolace střechy (Atribut objektu!) | Izolace tepelné | MINERÁLNÍ VATA | 1864Des0000021623 | m3 | Deska | NEW | no | 0.306 | 1.02 | 0.306 | 0.031 | 2.64 | 0.031 | 0.3 | 0.1 | NEMSOK - Kód prvku: TI06.06.2001; Požární odolnost: A1; Součinitel prostupu tepla: 0.036; Součinitel difúzního odporu: 1; Způsob spojení vrstev: Lepený + mechanicky kotvený
 | Půdorys 5.NP | FLOOR | PIR | yes | Izolace střechy (Atribut objektu!) | Izolace tepelné | PIR | 1866Des0000000003 | m3 | Deska | NEW | no | 266.191 | 14.764 | 266.191 | 69.21 | 67.38 | 69.21 | 18.03 | 0.26 | NEMSOK - Kód prvku: TI05.06.1001; Požární odolnost: E; Systém kotvení: Mechanicky kotvený + přitížený; Součinitel prostupu tepla: 0.022; Součinitel difúzního odporu: 150; Způsob spojení vrstev: Lepený + mechanicky kotvený
 | Půdorys 6.NP | FLOOR | PZD | yes | Betonová deska (Atribut objektu!) | Betonářské práce | PZD | 1954Des0000000367 | m3 | Deska | EXISTING | yes | 56.7 | 6.3 | 56.7 | 3.969 | 30.6 | 3.969 | 9 | 0.07
 | Půdorys 6.NP | FLOOR | PZD | yes | Betonová deska (Atribut objektu!) | Betonářské práce | PZD | 1954Des0000000370 | m3 | Deska | EXISTING | yes | 28.755 | 3.5 | 28.215 | 2.013 | 23.7 | 1.975 | 8.216 | 0.07
 | Půdorys 6.NP | FLOOR | MINERÁLNÍ VATA | yes | Izolace střechy (Atribut objektu!) | Izolace tepelné | MINERÁLNÍ VATA | 1964Des0000003521 | m3 | Deska | NEW | no | 0.108 | 0.204 | 0.107 | 0.016 | 1.454 | 0.016 | 0.529 | 0.15 | NEMSOK - Kód prvku: TI06.07.2001; Požární odolnost: A1; Součinitel prostupu tepla: 0.036; Součinitel difúzního odporu: 1; Způsob spojení vrstev: Lepený
 | Půdorys 6.NP | FLOOR | MINERÁLNÍ VATA | yes | Izolace střechy (Atribut objektu!) | Izolace tepelné | MINERÁLNÍ VATA | 1964Des0000003506 | m3 | Deska | NEW | no | 0.157 | 0.35 | 0.159 | 0.024 | 2.171 | 0.024 | 0.45 | 0.15 | NEMSOK - Kód prvku: TI06.07.2001; Požární odolnost: A1; Součinitel prostupu tepla: 0.036; Součinitel difúzního odporu: 1; Způsob spojení vrstev: Lepený
 | Půdorys 6.NP | FLOOR | MINERÁLNÍ VATA | yes | Izolace střechy (Atribut objektu!) | Izolace tepelné | MINERÁLNÍ VATA | 1964Des0000003368 | m3 | Deska | NEW | no | 0.72 | 0.6 | 0.72 | 0.072 | 3.6 | 0.072 | 1.2 | 0.1 | NEMSOK - Kód prvku: TI06.07.2001; Požární odolnost: A1; Součinitel prostupu tepla: 0.036; Součinitel difúzního odporu: 1; Způsob spojení vrstev: Lepený
 | Půdorys 6.NP | FLOOR | MINERÁLNÍ VATA | yes | Izolace střechy (Atribut objektu!) | Izolace tepelné | MINERÁLNÍ VATA | 1964Des0000003496 | m3 | Deska | NEW | no | 26.475 | 10.96 | 26.476 | 2.648 | 138.08 | 2.648 | 2.416 | 0.1 | NEMSOK - Kód prvku: TI06.07.2001; Požární odolnost: A1; Součinitel prostupu tepla: 0.036; Součinitel difúzního odporu: 1; Způsob spojení vrstev: Lepený + mechanicky kotvený
4 x  | Půdorys 6.NP | ROOF | ASFALTOVÁ HYDROIZOLACE 0.01 m, KAČÍREK 0.06 m
 | Půdorys 6.NP | FLOOR | SPÁDOVÉ KLÍNY PIR 3% | yes | Spádové klíny (Atribut objektu!) | Izolace tepelné | SPÁDOVÉ KLÍNY PIR 3% | 1964Des0000003520 | m3 | Deska | NEW | no | 254.665 | 1.515 | 254.139 | 137.908 | 71.772 | 137.622 | 168.096 | 0.542 | NEMSOK - Kód prvku: TI05.07.2001; Požární odolnost: E; Systém kotvení: Lepený + přitížený; Součinitel prostupu tepla: 0.022; Součinitel difúzního odporu: 150; Způsob spojení vrstev: Lepený
 | Půdorys 6.NP | FLOOR | PIR | yes | Izolace střechy (Atribut objektu!) | Izolace tepelné | PIR | 1966Des0000000010 | m3 | Deska | NEW | no | 85.62 | 10 | 84.54 | 22.261 | 37.7 | 21.98 | 8.562 | 0.26 | NEMSOK - Kód prvku: TI05.07.1002; Požární odolnost: E; Systém kotvení: Mechanicky kotvený + přitížený; Součinitel prostupu tepla: 0.022; Součinitel difúzního odporu: 150; Způsob spojení vrstev: Lepený + mechanicky kotvený
5 x  | Půdorys střechy | ROOF | ASFALTOVÁ HYDROIZOLACE 0.01 m, KAČÍREK 0.06 m
 | Půdorys střechy | FLOOR | SPÁDOVÉ KLÍNY PIR 3% | yes | Spádové klíny (Atribut objektu!) | Izolace tepelné | SPÁDOVÉ KLÍNY PIR 3% | 2481Des0000000210 | m3 | Deska | NEW | no | 78.902 | 1.335 | 78.938 | 33.16 | 41.14 | 33.16 | 59.103 | 0.42 | NEMSOK - Kód prvku: TI05.08.2001; Požární odolnost: E; Systém kotvení: Lepený + přitížený; Součinitel prostupu tepla: 0.022; Součinitel difúzního odporu: 150; Způsob spojení vrstev: Lepený

# IfcStair (20)
Material: Pøímé schodiötì
NEMSOK - Materiál: Pøímé schodiötì; Jednotka: Kus; Název_objektu: Schodiště
Name | In | Allright_Stavebni_dil_ID | NumberOfRiser | RiserHeight (m) | TreadLength (m) | NumberOfTreads
 | Půdorys 1.PP | 1352Sch0000001694 | 22 | 1.5 | 3 | 22
 | Půdorys 1.PP | 1352Sch0000008528 | 22 | 1.5 | 3 | 22
 | Půdorys 1.PP | 1352Sch0798427628 | 22 | 1.5 | 3 | 22
 | Půdorys 1.NP | 1452Sch0000001467 | 24 | 1.5 | 3 | 24
 | Půdorys 1.NP | 1452Sch0798422648 | 24 | 1.5 | 3 | 24
 | Půdorys 1.NP | 1452Sch0798426399 | 3 | 1.5 | 3 | 3
 | Půdorys 1.NP | 1452Sch0798426078 | 21 | 1.5 | 3 | 21
 | Půdorys 2.NP | 1552Sch0000001469 | 22 | 1.5 | 3 | 22
 | Půdorys 2.NP | 1552Sch0798423115 | 24 | 1.5 | 3 | 24
 | Půdorys 2.NP | 1552Sch0798428154 | 24 | 1.5 | 3 | 24
 | Půdorys 3.NP | 1652Sch0798423485 | 22 | 1.5 | 3 | 22
 | Půdorys 3.NP | 1652Sch0798427810 | 22 | 1.5 | 3 | 22
 | Půdorys 3.NP | 1652Sch0798428744 | 22 | 1.5 | 3 | 22
 | Půdorys 4.NP | 1752Sch0000001503 | 22 | 1.5 | 3 | 22
 | Půdorys 4.NP | 1752Sch0000009871 | 22 | 1.5 | 3 | 22
 | Půdorys 5.NP | 1852Sch0000001480 | 24 | 1.5 | 3 | 24
 | Půdorys 5.NP | 1852Sch0000001994 | 3 | 1.333 | 3 | 2
 | Půdorys 5.NP | 1852Sch0798426241 | 6 | 1.85 | 2.5 | 5
 | Půdorys 5.NP | 1852Sch0798428093 | 2 | 1 | 3 | 1
 | Půdorys 6.NP | 1952Sch0000000204 | 4 | 1.75 | 2.5 | 4

# IfcWall (2385)
NEMSOK - Object Layer Attributes #1, 2D interakce: yes
Name | In | Material | Faktor | Označení | Požární odolnost | Allright_Stavebni_dil_ID | Jednotka | Název_objektu | Object Layer Attributes #1, Status | Object Layer Attributes #1, Práce | Object Layer Attributes #1, Materiál | Object Layer Attributes #1, Staticky nosná konstrukce | Object Layer Attributes #1, Allright_Stavebni_dil_ID | Object Layer Attributes #1, Jednotka | Object Layer Attributes #1, Název_objektu | ThermalTransmittance (W/K/m2) | Width (m) | GrossSideArea (m2) | NetSideArea (m2) | GrossVolume (m3) | Length (m) | NetVolume (m3) | GrossFootprintArea (m2) | Height (m)
ZDIVO Z CDm | Půdorys 1.PP | ZDIVO Z CDm 0.125 m | 1 | ZDIVO Z CDm | A | 1302HWa0000000547 | m3 | Celá stěna | Stávající | Zednické práce | ZDIVO Z CDm | yes | 1302Stě0000000548 | m3 | Stěna | 0 | 0.125 | 9.76 | 5.819 | 1.22 | 3.2 | 0.727 | 0.4 | 3.05
ZELEZOBETONOVÁ KCE | Půdorys 1.PP | ZELEZOBETONOVÁ KCE 0.25 m, LIGNOPOR 0.025 m, PÓROBETONOVÉ ZDIVO 0.08 m | 1 | ZELEZOBETONOVÁ KCE | A | 1302HWa0000000384 | m3 | Celá stěna | Stávající | Betonářské práce | ZELEZOBETONOVÁ KCE |  | 1302Stě0000000446 | m3 | Stěna | 0 | 0.355 | 4.92 | 4.92 | 1.487 | 1.2 | 1.487 | 0.426 | 4.1 | NEMSOK - Object Layer Attributes #2, 2D interakce: yes; Object Layer Attributes #2, Status: Stávající; Object Layer Attributes #2, Práce: Zateplovací systémy; Object Layer Attributes #2, Materiál: LIGNOPOR; Object Layer Attributes #2, Allright_Stavebni_dil_ID: 1302Stě0000000444; Object Layer Attributes #2, Jednotka: m2; Object Layer Attributes #2, Název_objektu: Stěna; Object Layer Attributes #3, 2D interakce: yes; Object Layer Attributes #3, Status: Stávající; Object Layer Attributes #3, Práce: Zednické práce; Object Layer Attributes #3, Materiál: PÓROBETONOVÉ ZDIVO; Object Layer Attributes #3, Allright_Stavebni_dil_ID: 1302Stě0000000442; Object Layer Attributes #3, Jednotka: m2; Object Layer Attributes #3, Název_objektu: Stěna; Pset_WallCommon - LoadBearing: yes
ZELEZOBETONOVÁ KCE | Půdorys 1.PP | ZELEZOBETONOVÁ KCE 0.2 m | 1 | ZELEZOBETONOVÁ KCE | A | 1302HWa0000000022 | m3 | Celá stěna | Stávající | Betonářské práce | ZELEZOBETONOVÁ KCE |  | 1302Stě0000000037 | m3 | Stěna | 0 | 0.2 | 9.824 | 9.824 | 1.965 | 3.2 | 1.965 | 0.64 | 3.07
ZELEZOBETONOVÁ KCE | Půdorys 1.PP | ZELEZOBETONOVÁ KCE 0.2 m | 1 | ZELEZOBETONOVÁ KCE | A | 1302HWa0000000072 | m3 | Celá stěna | Stávající | Betonářské práce | ZELEZOBETONOVÁ KCE |  | 1302Stě0000000129 | m3 | Stěna | 0 | 0.2 | 16.578 | 16.578 | 3.316 | 5.4 | 3.316 | 1.08 | 3.07
ZELEZOBETONOVÁ KCE | Půdorys 1.PP | ZELEZOBETONOVÁ KCE 0.2 m | 1 | ZELEZOBETONOVÁ KCE | A | 1302HWa0000000074 | m3 | Celá stěna | Stávající | Betonářské práce | ZELEZOBETONOVÁ KCE |  | 1302Stě0000000077 | m3 | Stěna | 0 | 0.2 | 16.578 | 16.578 | 3.316 | 5.4 | 3.316 | 1.08 | 3.07
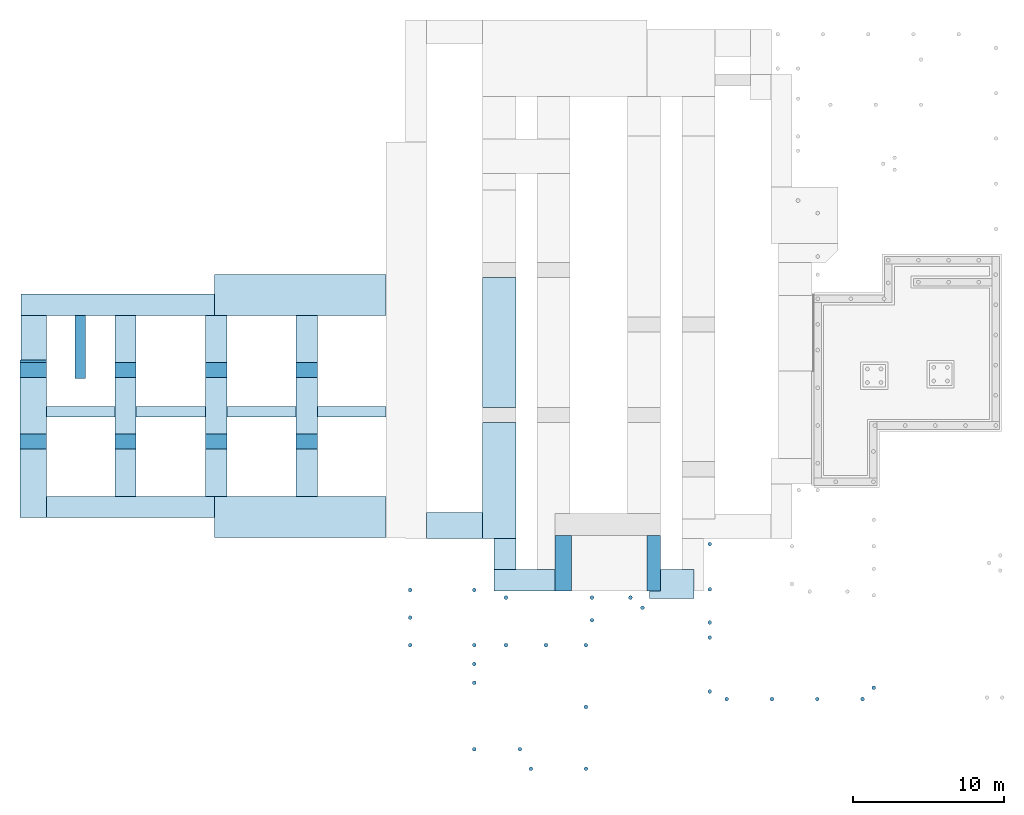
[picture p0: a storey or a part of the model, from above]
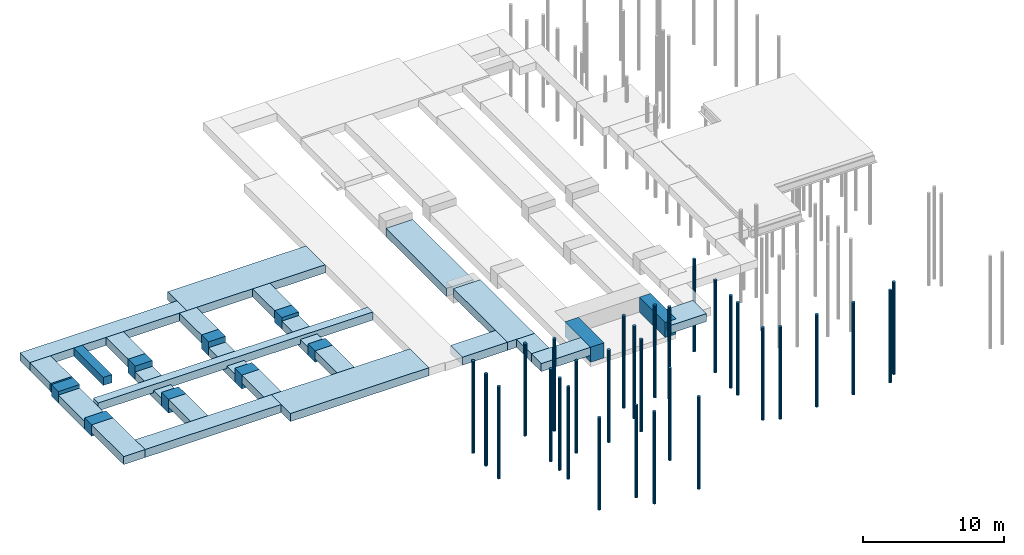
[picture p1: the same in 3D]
Properties of the parts of a building model (IFC4), part 23 of 45

# IfcWall (2385)
Name | In | Material | Faktor | Označení | Požární odolnost | Allright_Stavebni_dil_ID | Jednotka | Název_objektu | Object Layer Attributes #1, Status | Object Layer Attributes #1, Práce | Object Layer Attributes #1, Materiál | Object Layer Attributes #1, Staticky nosná konstrukce | Object Layer Attributes #1, Allright_Stavebni_dil_ID | Object Layer Attributes #1, Jednotka | Object Layer Attributes #1, Název_objektu | ThermalTransmittance (W/K/m2) | Width (m) | GrossSideArea (m2) | NetSideArea (m2) | GrossVolume (m3) | Length (m) | NetVolume (m3) | GrossFootprintArea (m2) | Height (m)
ZELEZOBETONOVÁ KCE | Půdorys 1.PP | ZELEZOBETONOVÁ KCE 0.25 m, LIGNOPOR 0.025 m, PÓROBETONOVÉ ZDIVO 0.08 m | 1 | ZELEZOBETONOVÁ KCE | A | 1302HWa0000000396 | m3 | Celá stěna | Stávající | Betonářské práce | ZELEZOBETONOVÁ KCE |  | 1302Stě0000000404 | m3 | Stěna | 0 | 0.355 | 30.975 | 30.976 | 9.269 | 7.493 | 9.269 | 2.654 | 4.1 | NEMSOK - Object Layer Attributes #2, 2D interakce: yes; Object Layer Attributes #2, Status: Stávající; Object Layer Attributes #2, Práce: Zateplovací systémy; Object Layer Attributes #2, Materiál: LIGNOPOR; Object Layer Attributes #2, Allright_Stavebni_dil_ID: 1302Stě0000000402; Object Layer Attributes #2, Jednotka: m2; Object Layer Attributes #2, Název_objektu: Stěna; Object Layer Attributes #3, 2D interakce: yes; Object Layer Attributes #3, Status: Stávající; Object Layer Attributes #3, Práce: Zednické práce; Object Layer Attributes #3, Materiál: PÓROBETONOVÉ ZDIVO; Object Layer Attributes #3, Allright_Stavebni_dil_ID: 1302Stě0000000400; Object Layer Attributes #3, Jednotka: m2; Object Layer Attributes #3, Název_objektu: Stěna; Pset_WallCommon - LoadBearing: yes
ZELEZOBETONOVÁ KCE | Půdorys 1.PP | ZELEZOBETONOVÁ KCE 0.25 m, LIGNOPOR 0.025 m, PÓROBETONOVÉ ZDIVO 0.08 m | 1 | ZELEZOBETONOVÁ KCE | A | 1302HWa0000000377 | m3 | Celá stěna | Stávající | Betonářské práce | ZELEZOBETONOVÁ KCE |  | 1302Stě0000000465 | m3 | Stěna | 0 | 0.355 | 5.33 | 5.33 | 1.611 | 1.3 | 1.611 | 0.461 | 4.1 | NEMSOK - Object Layer Attributes #2, 2D interakce: yes; Object Layer Attributes #2, Status: Stávající; Object Layer Attributes #2, Práce: Zateplovací systémy; Object Layer Attributes #2, Materiál: LIGNOPOR; Object Layer Attributes #2, Allright_Stavebni_dil_ID: 1302Stě0000000467; Object Layer Attributes #2, Jednotka: m2; Object Layer Attributes #2, Název_objektu: Stěna; Object Layer Attributes #3, 2D interakce: yes; Object Layer Attributes #3, Status: Stávající; Object Layer Attributes #3, Práce: Zednické práce; Object Layer Attributes #3, Materiál: PÓROBETONOVÉ ZDIVO; Object Layer Attributes #3, Allright_Stavebni_dil_ID: 1302Stě0000000469; Object Layer Attributes #3, Jednotka: m2; Object Layer Attributes #3, Název_objektu: Stěna; Pset_WallCommon - LoadBearing: yes
ZELEZOBETONOVÁ KCE | Půdorys 1.PP | ZELEZOBETONOVÁ KCE 0.25 m, LIGNOPOR 0.025 m, PÓROBETONOVÉ ZDIVO 0.08 m | 1 | ZELEZOBETONOVÁ KCE | A | 1302HWa0000000386 | m3 | Celá stěna | Stávající | Betonářské práce | ZELEZOBETONOVÁ KCE |  | 1302Stě0000000429 | m3 | Stěna | 0 | 0.355 | 154.447 | 154.447 | 46.218 | 37.47 | 45.543 | 13.234 | 4.1 | NEMSOK - Object Layer Attributes #2, 2D interakce: yes; Object Layer Attributes #2, Status: Stávající; Object Layer Attributes #2, Práce: Zateplovací systémy; Object Layer Attributes #2, Materiál: LIGNOPOR; Object Layer Attributes #2, Allright_Stavebni_dil_ID: 1302Stě0000000427; Object Layer Attributes #2, Jednotka: m2; Object Layer Attributes #2, Název_objektu: Stěna; Object Layer Attributes #3, 2D interakce: yes; Object Layer Attributes #3, Status: Stávající; Object Layer Attributes #3, Práce: Zednické práce; Object Layer Attributes #3, Materiál: PÓROBETONOVÉ ZDIVO; Object Layer Attributes #3, Allright_Stavebni_dil_ID: 1302Stě0000000425; Object Layer Attributes #3, Jednotka: m2; Object Layer Attributes #3, Název_objektu: Stěna; Pset_WallCommon - LoadBearing: yes
ZELEZOBETONOVÁ KCE | Půdorys 1.PP | ZELEZOBETONOVÁ KCE 0.25 m, LIGNOPOR 0.025 m, PÓROBETONOVÉ ZDIVO 0.08 m | 1 | ZELEZOBETONOVÁ KCE | A | 1302HWa0000000388 | m3 | Celá stěna | Stávající | Betonářské práce | ZELEZOBETONOVÁ KCE |  | 1302Stě0000000394 | m3 | Stěna | 0 | 0.355 | 30.771 | 30.771 | 9.207 | 7.443 | 9.207 | 2.636 | 4.1 | NEMSOK - Object Layer Attributes #2, 2D interakce: yes; Object Layer Attributes #2, Status: Stávající; Object Layer Attributes #2, Práce: Zateplovací systémy; Object Layer Attributes #2, Materiál: LIGNOPOR; Object Layer Attributes #2, Allright_Stavebni_dil_ID: 1302Stě0000000392; Object Layer Attributes #2, Jednotka: m2; Object Layer Attributes #2, Název_objektu: Stěna; Object Layer Attributes #3, 2D interakce: yes; Object Layer Attributes #3, Status: Stávající; Object Layer Attributes #3, Práce: Zednické práce; Object Layer Attributes #3, Materiál: PÓROBETONOVÉ ZDIVO; Object Layer Attributes #3, Allright_Stavebni_dil_ID: 1302Stě0000000390; Object Layer Attributes #3, Jednotka: m2; Object Layer Attributes #3, Název_objektu: Stěna; Pset_WallCommon - LoadBearing: yes
ZELEZOBETONOVÁ KCE | Půdorys 1.PP | ZELEZOBETONOVÁ KCE 0.2 m | 1 | ZELEZOBETONOVÁ KCE | A | 1302HWa0000000002 | m3 | Celá stěna | Stávající | Betonářské práce | ZELEZOBETONOVÁ KCE |  | 1302Stě0000000009 | m3 | Stěna | 0 | 0.2 | 9.824 | 9.824 | 1.965 | 3.2 | 1.965 | 0.64 | 3.07
ZELEZOBETONOVÁ KCE | Půdorys 1.PP | ZELEZOBETONOVÁ KCE 0.2 m | 1 | ZELEZOBETONOVÁ KCE | A | 1302HWa0000000046 | m3 | Celá stěna | Stávající | Betonářské práce | ZELEZOBETONOVÁ KCE |  | 1302Stě0000000069 | m3 | Stěna | 0 | 0.2 | 16.578 | 16.578 | 3.316 | 5.4 | 3.316 | 1.08 | 3.07
ZELEZOBETONOVÁ KCE | Půdorys 1.PP | ZELEZOBETONOVÁ KCE 0.2 m | 1 | ZELEZOBETONOVÁ KCE | A | 1302HWa0000000082 | m3 | Celá stěna | Stávající | Betonářské práce | ZELEZOBETONOVÁ KCE |  | 1302Stě0000000131 | m3 | Stěna | 0 | 0.2 | 16.578 | 16.578 | 3.316 | 5.4 | 3.316 | 1.08 | 3.07
ZELEZOBETONOVÁ KCE | Půdorys 1.PP | ZELEZOBETONOVÁ KCE 0.15 m |  | ZELEZOBETONOVÁ KCE | A | 1302HWa0798451170 | m3 | Celá stěna | Stávající | Betonářské práce | ZELEZOBETONOVÁ KCE |  | 1302Stě0798451188 | m3 | Stěna | 0 | 0.15 | 5.016 | 5.016 | 0.752 | 1.2 | 0.752 | 0.18 | 4.18
ZELEZOBETONOVÁ KCE | Půdorys 1.PP | ZELEZOBETONOVÁ KCE 0.15 m |  | ZELEZOBETONOVÁ KCE | A | 1302HWa0798451174 | m3 | Celá stěna | Stávající | Betonářské práce | ZELEZOBETONOVÁ KCE |  | 1302Stě0798451186 | m3 | Stěna | 0 | 0.15 | 2.717 | 2.717 | 0.408 | 0.65 | 0.408 | 0.097 | 4.18
ZELEZOBETONOVÁ KCE | Půdorys 1.PP | ZELEZOBETONOVÁ KCE 0.15 m |  | ZELEZOBETONOVÁ KCE | A | 1302HWa0798451176 | m3 | Celá stěna | Stávající | Betonářské práce | ZELEZOBETONOVÁ KCE |  | 1302Stě0798451184 | m3 | Stěna | 0 | 0.15 | 3.344 | 3.344 | 0.502 | 0.8 | 0.502 | 0.12 | 4.18
ZELEZOBETONOVÁ KCE | Půdorys 1.PP | ZELEZOBETONOVÁ KCE 0.15 m |  | ZELEZOBETONOVÁ KCE | A | 1302HWa0798451172 | m3 | Celá stěna | Stávající | Betonářské práce | ZELEZOBETONOVÁ KCE |  | 1302Stě0798451181 | m3 | Stěna | 0 | 0.15 | 4.389 | 4.389 | 0.658 | 1.05 | 0.658 | 0.158 | 4.18
ZELEZOBETONOVÁ KCE | Půdorys 1.PP | ZELEZOBETONOVÁ KCE 0.15 m |  | ZELEZOBETONOVÁ KCE | A | 1302HWa0798452796 | m3 | Celá stěna | Stávající | Betonářské práce | ZELEZOBETONOVÁ KCE |  | 1302Stě0798452797 | m3 | Stěna | 0 | 0.15 | 1.418 | 1.418 | 0.213 | 0.75 | 0.213 | 0.113 | 1.89
ZELEZOBETONOVÁ KCE | Půdorys 1.PP | ZELEZOBETONOVÁ KCE 0.15 m |  | ZELEZOBETONOVÁ KCE | A | 1302HWa0798451155 | m3 | Celá stěna | Stávající | Betonářské práce | ZELEZOBETONOVÁ KCE |  | 1302Stě0798451159 | m3 | Stěna | 0 | 0.15 | 1.134 | 1.134 | 0.17 | 0.6 | 0.17 | 0.09 | 1.89
ZELEZOBETONOVÁ KCE | Půdorys 1.PP | ZELEZOBETONOVÁ KCE 0.15 m |  | ZELEZOBETONOVÁ KCE | A | 1302HWa0798452079 | m3 | Celá stěna | Stávající | Betonářské práce | ZELEZOBETONOVÁ KCE |  | 1302Stě0798452081 | m3 | Stěna | 0 | 0.15 | 2.268 | 2.268 | 0.34 | 1.2 | 0.34 | 0.18 | 1.89
ZELEZOBETONOVÁ KCE | Půdorys 1.PP | ZELEZOBETONOVÁ KCE 0.15 m |  | ZELEZOBETONOVÁ KCE | A | 1302HWa0798451151 | m3 | Celá stěna | Stávající | Betonářské práce | ZELEZOBETONOVÁ KCE |  | 1302Stě0798451169 | m3 | Stěna | 0 | 0.15 | 1.985 | 1.985 | 0.298 | 1.05 | 0.298 | 0.158 | 1.89
ZELEZOBETONOVÁ KCE | Půdorys 1.PP | ZELEZOBETONOVÁ KCE | 1 | ZELEZOBETONOVÁ KCE | A | 1302HWa0798452479 | m3 | Celá stěna | Stávající | Betonářské práce | ZELEZOBETONOVÁ KCE |  | 1302Stě0798452482 | m3 | Stěna | 0 | 0.355 | 15.898 | 15.898 | 4.573 | 3.778 | 4.573 | 1.307 | 4.1 | NEMSOK - Object Layer Attributes #2, 2D interakce: yes; Object Layer Attributes #2, Status: Stávající; Object Layer Attributes #2, Práce: Zateplovací systémy; Object Layer Attributes #2, Materiál: LIGNOPOR; Object Layer Attributes #2, Allright_Stavebni_dil_ID: 1302Stě0798452481; Object Layer Attributes #2, Jednotka: m2; Object Layer Attributes #2, Název_objektu: Stěna; Object Layer Attributes #3, 2D interakce: yes; Object Layer Attributes #3, Status: Stávající; Object Layer Attributes #3, Práce: Zednické práce; Object Layer Attributes #3, Materiál: PÓROBETONOVÉ ZDIVO; Object Layer Attributes #3, Allright_Stavebni_dil_ID: 1302Stě0798452483; Object Layer Attributes #3, Jednotka: m2; Object Layer Attributes #3, Název_objektu: Stěna; Pset_WallCommon - LoadBearing: yes
ZELEZOBETONOVÁ KCE | Půdorys 1.PP | ZELEZOBETONOVÁ KCE 0.2 m |  | ZELEZOBETONOVÁ KCE | A | 1302HWa0798452744 | m3 | Celá stěna | Stávající | Betonářské práce | ZELEZOBETONOVÁ KCE |  | 1302Stě0798452745 | m3 | Stěna | 0 | 0.2 | 1.939 | 1.939 | 0.388 | 1.539 | 0.388 | 0.308 | 1.26
ZELEZOBETONOVÁ KCE | Půdorys 1.PP | ZELEZOBETONOVÁ KCE 0.2 m | 1 | ZELEZOBETONOVÁ KCE | A | 1302HWa0798452120 | m3 | Celá stěna | Stávající | Betonářské práce | ZELEZOBETONOVÁ KCE |  | 1302Stě0798452121 | m3 | Stěna | 0 | 0.2 | 2.191 | 2.191 | 0.438 | 1.739 | 0.438 | 0.348 | 1.26
ZELEZOBETONOVÁ KCE | Půdorys 1.PP | ZELEZOBETONOVÁ KCE 0.2 m | 1 | ZELEZOBETONOVÁ KCE | A | 1302HWa0798453272 | m3 | Celá stěna | Stávající | Betonářské práce | ZELEZOBETONOVÁ KCE |  | 1302Stě0798453273 | m3 | Stěna | 0 | 0.2 | 8.512 | 8.512 | 1.702 | 6.755 | 1.702 | 1.351 | 1.26
ZELEZOBETONOVÁ KCE | Půdorys 1.PP | ZELEZOBETONOVÁ KCE 0.25 m, LIGNOPOR 0.025 m, PÓROBETONOVÉ ZDIVO 0.08 m |  | ZELEZOBETONOVÁ KCE | A | 1302HWa0798452532 | m3 | Celá stěna | Stávající | Betonářské práce | ZELEZOBETONOVÁ KCE | no | 1302Stě0798452536 | m3 | Stěna | 0 | 0.355 | 23.297 | 23.297 | 7.238 | 6.954 | 7.092 | 2.469 | 3.35 | NEMSOK - Object Layer Attributes #2, 2D interakce: yes; Object Layer Attributes #2, Status: Stávající; Object Layer Attributes #2, Práce: Zateplovací systémy; Object Layer Attributes #2, Materiál: LIGNOPOR; Object Layer Attributes #2, Allright_Stavebni_dil_ID: 1302Stě0798452535; Object Layer Attributes #2, Jednotka: m2; Object Layer Attributes #2, Název_objektu: Stěna; Object Layer Attributes #3, 2D interakce: yes; Object Layer Attributes #3, Status: Stávající; Object Layer Attributes #3, Práce: Zednické práce; Object Layer Attributes #3, Materiál: PÓROBETONOVÉ ZDIVO; Object Layer Attributes #3, Allright_Stavebni_dil_ID: 1302Stě0798453376; Object Layer Attributes #3, Jednotka: m2; Object Layer Attributes #3, Název_objektu: Stěna; Object Layer Attributes #2, Staticky nosná konstrukce: no; Object Layer Attributes #3, Staticky nosná konstrukce: no; Pset_WallCommon - LoadBearing: yes
ZELEZOBETONOVÁ KCE | Půdorys 1.PP | ZELEZOBETONOVÁ KCE 0.25 m, LIGNOPOR 0.025 m, PÓROBETONOVÉ ZDIVO 0.08 m | 1 | ZELEZOBETONOVÁ KCE | A | 1302HWa0000000423 | m3 | Celá stěna | Stávající | Betonářské práce | ZELEZOBETONOVÁ KCE |  | 1302Stě0000000448 | m3 | Stěna | 0 | 0.355 | 18.86 | 18.86 | 6.29 | 4.85 | 5.676 | 1.809 | 4.1 | NEMSOK - Object Layer Attributes #2, 2D interakce: yes; Object Layer Attributes #2, Status: Stávající; Object Layer Attributes #2, Práce: Zateplovací systémy; Object Layer Attributes #2, Materiál: LIGNOPOR; Object Layer Attributes #2, Allright_Stavebni_dil_ID: 1302Stě0000000440; Object Layer Attributes #2, Jednotka: m2; Object Layer Attributes #2, Název_objektu: Stěna; Object Layer Attributes #3, 2D interakce: yes; Object Layer Attributes #3, Status: Stávající; Object Layer Attributes #3, Práce: Zednické práce; Object Layer Attributes #3, Materiál: PÓROBETONOVÉ ZDIVO; Object Layer Attributes #3, Allright_Stavebni_dil_ID: 1302Stě0000000438; Object Layer Attributes #3, Jednotka: m2; Object Layer Attributes #3, Název_objektu: Stěna; Pset_WallCommon - LoadBearing: yes
PREFA ŽB ENERGOKANÁL | Půdorys 1.PP | PREFA ŽB ENERGOKANÁL 0.1 m |  | PREFA ŽB ENERGOKANÁL | A | 1302HWa0798451450 | m3 | Celá stěna | Stávající | Betonářské práce | PREFA ŽB ENERGOKANÁL | yes | 1302Stě0798451463 | m3 | Stěna | 0 | 0.1 | 2.228 | 2.228 | 0.223 | 3.714 | 0.223 | 0.371 | 0.6
PREFA ŽB ENERGOKANÁL | Půdorys 1.PP | PREFA ŽB ENERGOKANÁL 0.1 m |  | PREFA ŽB ENERGOKANÁL | A | 1302HWa0798451452 | m3 | Celá stěna | Stávající | Betonářské práce | PREFA ŽB ENERGOKANÁL | yes | 1302Stě0798451459 | m3 | Stěna | 0 | 0.1 | 2.228 | 2.228 | 0.223 | 3.714 | 0.223 | 0.371 | 0.6
PREFA ŽB ENERGOKANÁL | Půdorys 1.PP | PREFA ŽB ENERGOKANÁL 0.1 m |  | PREFA ŽB ENERGOKANÁL | A | 1302HWa0798451454 | m3 | Celá stěna | Stávající | Betonářské práce | PREFA ŽB ENERGOKANÁL | yes | 1302Stě0798451461 | m3 | Stěna | 0 | 0.1 | 2.228 | 2.228 | 0.223 | 3.714 | 0.223 | 0.371 | 0.6
PREFA ŽB ENERGOKANÁL | Půdorys 1.PP | PREFA ŽB ENERGOKANÁL 0.1 m |  | PREFA ŽB ENERGOKANÁL | A | 1302HWa0798451456 | m3 | Celá stěna | Stávající | Betonářské práce | PREFA ŽB ENERGOKANÁL | yes | 1302Stě0798451473 | m3 | Stěna | 0 | 0.1 | 2.228 | 2.228 | 0.223 | 3.714 | 0.223 | 0.371 | 0.6
ZDIVO Z CDm | Půdorys 1.PP | ZDIVO Z CDm 0.125 m | 1 | ZDIVO Z CDm | A | 1302HWa0798454813 | m3 | Celá stěna | Stávající | Zednické práce | ZDIVO Z CDm | yes | 1302Stě0798454814 | m3 | Stěna | 0 | 0.125 | 9.824 | 8.006 | 1.228 | 3.2 | 1.001 | 0.4 | 3.07
ZDIVO Z CDm | Půdorys 1.PP | ZDIVO Z CDm 0.125 m | 1 | ZDIVO Z CDm | A | 1302HWa0798454822 | m3 | Celá stěna | Stávající | Zednické práce | ZDIVO Z CDm | yes | 1302Stě0798454823 | m3 | Stěna | 0 | 0.125 | 9.824 | 9.824 | 1.228 | 3.2 | 1.228 | 0.4 | 3.07
ZDIVO Z CDm | Půdorys 1.PP | ZDIVO Z CDm 0.125 m | 1 | ZDIVO Z CDm | A | 1302HWa0798454831 | m3 | Celá stěna | Stávající | Zednické práce | ZDIVO Z CDm | yes | 1302Stě0798454832 | m3 | Stěna | 0 | 0.125 | 9.824 | 9.824 | 1.228 | 3.2 | 1.228 | 0.4 | 3.07
ZDIVO Z CDm | Půdorys 1.PP | ZDIVO Z CDm 0.125 m | 1 | ZDIVO Z CDm | A | 1302HWa0798454840 | m3 | Celá stěna | Stávající | Zednické práce | ZDIVO Z CDm | yes | 1302Stě0798454841 | m3 | Stěna | 0 | 0.125 | 9.824 | 8.006 | 1.228 | 3.2 | 1.001 | 0.4 | 3.07
ZDIVO Z CDm | Půdorys 1.PP | ZDIVO Z CDm 0.125 m | 1 | ZDIVO Z CDm | A | 1302HWa0798454849 | m3 | Celá stěna | Stávající | Zednické práce | ZDIVO Z CDm | yes | 1302Stě0798454850 | m3 | Stěna | 0 | 0.125 | 9.824 | 6.592 | 1.228 | 3.2 | 0.824 | 0.4 | 3.07
ZDIVO Z CDm | Půdorys 1.PP | ZDIVO Z CDm 0.125 m | 1 | ZDIVO Z CDm | A | 1302HWa0798454858 | m3 | Celá stěna | Stávající | Zednické práce | ZDIVO Z CDm | yes | 1302Stě0798454859 | m3 | Stěna | 0 | 0.125 | 9.824 | 6.592 | 1.228 | 3.2 | 0.824 | 0.4 | 3.07
ZDIVO Z CDm | Půdorys 1.PP | ZDIVO Z CDm 0.125 m | 1 | ZDIVO Z CDm | A | 1302HWa0798454867 | m3 | Celá stěna | Stávající | Zednické práce | ZDIVO Z CDm | yes | 1302Stě0798454868 | m3 | Stěna | 0 | 0.125 | 16.578 | 16.578 | 2.072 | 5.4 | 2.072 | 0.675 | 3.07
ZDIVO Z CDm | Půdorys 1.PP | ZDIVO Z CDm 0.125 m | 1 | ZDIVO Z CDm | A | 1302HWa0798454876 | m3 | Celá stěna | Stávající | Zednické práce | ZDIVO Z CDm | yes | 1302Stě0798454877 | m3 | Stěna | 0 | 0.125 | 18.65 | 18.65 | 2.331 | 6.075 | 2.331 | 0.759 | 3.07
ZDIVO Z CDm | Půdorys 1.PP | ZDIVO Z CDm 0.125 m | 1 | ZDIVO Z CDm | A | 1302HWa0798454891 | m3 | Celá stěna | Stávající | Zednické práce | ZDIVO Z CDm | yes | 1302Stě0798454892 | m3 | Stěna | 0 | 0.125 | 18.65 | 18.65 | 2.331 | 6.075 | 2.331 | 0.759 | 3.07
ZDIVO Z CDm | Půdorys 1.PP | ZDIVO Z CDm 0.125 m | 1 | ZDIVO Z CDm | A | 1302HWa0798454906 | m3 | Celá stěna | Stávající | Zednické práce | ZDIVO Z CDm | yes | 1302Stě0798454907 | m3 | Stěna | 0 | 0.125 | 16.578 | 16.578 | 2.072 | 5.4 | 2.072 | 0.675 | 3.07
ZDIVO Z CDm | Půdorys 1.PP | ZDIVO Z CDm 0.125 m | 1 | ZDIVO Z CDm | A | 1302HWa0798454932 | m3 | Celá stěna | Stávající | Zednické práce | ZDIVO Z CDm | yes | 1302Stě0798454933 | m3 | Stěna | 0 | 0.125 | 12.741 | 12.741 | 1.593 | 4.15 | 1.593 | 0.519 | 3.07
ZDIVO Z CDm | Půdorys 1.PP | ZDIVO Z CDm 0.125 m | 1 | ZDIVO Z CDm | A | 1302HWa0798454943 | m3 | Celá stěna | Stávající | Zednické práce | ZDIVO Z CDm | yes | 1302Stě0798454944 | m3 | Stěna | 0 | 0.125 | 1.704 | 1.704 | 0.213 | 0.555 | 0.213 | 0.069 | 3.07
ZDIVO Z CDm | Půdorys 1.PP | ZDIVO Z CDm 0.125 m | 1 | ZDIVO Z CDm | A | 1302HWa0798454922 | m3 | Celá stěna | Stávající | Zednické práce | ZDIVO Z CDm | yes | 1302Stě0798454923 | m3 | Stěna | 0 | 0.125 | 22.027 | 20.209 | 2.753 | 7.175 | 2.526 | 0.897 | 3.07
ZDIVO Z CDm | Půdorys 1.PP | ZDIVO Z CDm 0.125 m | 1 | ZDIVO Z CDm | A | 1302HWa0798454915 | m3 | Celá stěna | Stávající | Zednické práce | ZDIVO Z CDm | yes | 1302Stě0798454916 | m3 | Stěna | 0 | 0.125 | 10.668 | 7.234 | 1.334 | 3.475 | 0.904 | 0.434 | 3.07
ZDIVO Z CDm | Půdorys 1.PP | ZDIVO Z CDm 0.125 m | 1 | ZDIVO Z CDm | A | 1302HWa0798454965 | m3 | Celá stěna | Stávající | Zednické práce | ZDIVO Z CDm | yes | 1302Stě0798454966 | m3 | Stěna | 0 | 0.125 | 0.921 | 0.921 | 0.115 | 0.3 | 0.115 | 0.038 | 3.07
ZDIVO Z CDm | Půdorys 1.PP | ZDIVO Z CDm 0.125 m | 1 | ZDIVO Z CDm | A | 1302HWa0798454977 | m3 | Celá stěna | Stávající | Zednické práce | ZDIVO Z CDm | yes | 1302Stě0798454978 | m3 | Stěna | 0 | 0.125 | 25.067 | 25.067 | 3.133 | 8.165 | 3.133 | 1.021 | 3.07
ZDIVO Z CDm | Půdorys 1.PP | ZDIVO Z CDm 0.125 m | 1 | ZDIVO Z CDm | A | 1302HWa0798455011 | m3 | Celá stěna | Stávající | Zednické práce | ZDIVO Z CDm | yes | 1302Stě0798455012 | m3 | Stěna | 0 | 0.125 | 2.303 | 2.303 | 0.288 | 0.75 | 0.288 | 0.094 | 3.07
ZDIVO Z CDm | Půdorys 1.PP | ZDIVO Z CDm 0.125 m | 1 | ZDIVO Z CDm | A | 1302HWa0798455037 | m3 | Celá stěna | Stávající | Zednické práce | ZDIVO Z CDm | yes | 1302Stě0798455038 | m3 | Stěna | 0 | 0.125 | 2.609 | 2.61 | 0.326 | 0.85 | 0.326 | 0.106 | 3.07
ZDIVO Z CDm | Půdorys 1.PP | ZDIVO Z CDm 0.125 m | 1 | ZDIVO Z CDm | A | 1302HWa0798455049 | m3 | Celá stěna | Stávající | Zednické práce | ZDIVO Z CDm | yes | 1302Stě0798455050 | m3 | Stěna | 0 | 0.125 | 16.578 | 16.578 | 2.072 | 5.4 | 2.072 | 0.675 | 3.07
ZDIVO Z CDm | Půdorys 1.PP | ZDIVO Z CDm 0.125 m | 1 | ZDIVO Z CDm | A | 1302HWa0798455075 | m3 | Celá stěna | Stávající | Zednické práce | ZDIVO Z CDm | yes | 1302Stě0798455076 | m3 | Stěna | 0 | 0.125 | 2.609 | 2.61 | 0.326 | 0.85 | 0.326 | 0.106 | 3.07
ZDIVO Z CDm | Půdorys 1.PP | ZDIVO Z CDm 0.125 m | 1 | ZDIVO Z CDm | A | 1302HWa0798455086 | m3 | Celá stěna | Stávající | Zednické práce | ZDIVO Z CDm | yes | 1302Stě0798455087 | m3 | Stěna | 0 | 0.125 | 9.44 | 7.622 | 1.18 | 3.075 | 0.953 | 0.384 | 3.07
ZDIVO Z CDm | Půdorys 1.PP | ZDIVO Z CDm 0.125 m | 1 | ZDIVO Z CDm | A | 1302HWa0798455100 | m3 | Celá stěna | Stávající | Zednické práce | ZDIVO Z CDm | yes | 1302Stě0798455101 | m3 | Stěna | 0 | 0.125 | 3.224 | 3.224 | 0.403 | 1.05 | 0.403 | 0.131 | 3.07
ZDIVO Z CDm | Půdorys 1.PP | ZDIVO Z CDm 0.125 m | 1 | ZDIVO Z CDm | A | 1302HWa0798455109 | m3 | Celá stěna | Stávající | Zednické práce | ZDIVO Z CDm | yes | 1302Stě0798455110 | m3 | Stěna | 0 | 0.125 | 11.512 | 11.513 | 1.439 | 3.75 | 1.439 | 0.469 | 3.07
ZDIVO Z CDm | Půdorys 1.PP | ZDIVO Z CDm 0.125 m | 1 | ZDIVO Z CDm | A | 1302HWa0798455121 | m3 | Celá stěna | Stávající | Zednické práce | ZDIVO Z CDm | yes | 1302Stě0798455122 | m3 | Stěna | 0 | 0.125 | 14.199 | 14.199 | 1.775 | 4.625 | 1.775 | 0.578 | 3.07
ZDIVO Z CDm | Půdorys 1.PP | ZDIVO Z CDm 0.125 m | 1 | ZDIVO Z CDm | A | 1302HWa0798455156 | m3 | Celá stěna | Stávající | Zednické práce | ZDIVO Z CDm | yes | 1302Stě0798455157 | m3 | Stěna | 0 | 0.125 | 6.524 | 3.09 | 0.815 | 2.125 | 0.386 | 0.266 | 3.07
ZDIVO Z CDm | Půdorys 1.PP | ZDIVO Z CDm 0.125 m | 1 | ZDIVO Z CDm | A | 1302HWa0798455022 | m3 | Celá stěna | Stávající | Zednické práce | ZDIVO Z CDm | yes | 1302Stě0798455023 | m3 | Stěna | 0 | 0.125 | 38.268 | 36.45 | 4.783 | 12.465 | 4.556 | 1.558 | 3.07
ZDIVO Z CDm | Půdorys 1.PP | ZDIVO Z CDm 0.125 m | 1 | ZDIVO Z CDm | A | 1302HWa0798455034 | m3 | Celá stěna | Stávající | Zednické práce | ZDIVO Z CDm | yes | 1302Stě0798455035 | m3 | Stěna | 0 | 0.125 | 28.858 | 23.202 | 3.607 | 9.4 | 2.9 | 1.175 | 3.07
ZDIVO Z CDm | Půdorys 1.PP | ZDIVO Z CDm 0.125 m | 1 | ZDIVO Z CDm | A | 1302HWa0798456006 | m3 | Celá stěna | Stávající | Zednické práce | ZDIVO Z CDm | yes | 1302Stě0798456007 | m3 | Stěna | 0 | 0.125 | 0.921 | 0.921 | 0.115 | 0.3 | 0.115 | 0.038 | 3.07
ZDIVO Z CDm | Půdorys 1.PP | ZDIVO Z CDm 0.125 m | 1 | ZDIVO Z CDm | A | 1302HWa0798456016 | m3 | Celá stěna | Stávající | Zednické práce | ZDIVO Z CDm | yes | 1302Stě0798456017 | m3 | Stěna | 0 | 0.125 | 1.09 | 1.09 | 0.136 | 0.355 | 0.136 | 0.044 | 3.07
ZDIVO Z CDm | Půdorys 1.PP | ZDIVO Z CDm 0.125 m | 1 | ZDIVO Z CDm | A | 1302HWa0798456027 | m3 | Celá stěna | Stávající | Zednické práce | ZDIVO Z CDm | yes | 1302Stě0798456028 | m3 | Stěna | 0 | 0.125 | 0.537 | 0.537 | 0.067 | 0.175 | 0.067 | 0.022 | 3.07
ZDIVO Z CDm | Půdorys 1.PP | ZDIVO Z CDm 0.125 m | 1 | ZDIVO Z CDm | A | 1302HWa0798456098 | m3 | Celá stěna | Stávající | Zednické práce | ZDIVO Z CDm | yes | 1302Stě0798456100 | m3 | Stěna | 0 | 0.125 | 2.303 | 2.303 | 0.288 | 0.75 | 0.288 | 0.094 | 3.07
ZDIVO Z CDm | Půdorys 1.PP | ZDIVO Z CDm 0.125 m | 1 | ZDIVO Z CDm | A | 1302HWa0798456125 | m3 | Celá stěna | Stávající | Zednické práce | ZDIVO Z CDm | yes | 1302Stě0798456127 | m3 | Stěna | 0 | 0.125 | 12.326 | 12.326 | 1.541 | 4.015 | 1.541 | 0.502 | 3.07
ZDIVO Z CDm | Půdorys 1.PP | ZDIVO Z CDm 0.125 m | 1 | ZDIVO Z CDm | A | 1302HWa0798456170 | m3 | Celá stěna | Stávající | Zednické práce | ZDIVO Z CDm | yes | 1302Stě0798456173 | m3 | Stěna | 0 | 0.125 | 0.537 | 0.537 | 0.067 | 0.175 | 0.067 | 0.022 | 3.07
ZDIVO Z CDm | Půdorys 1.PP | ZDIVO Z CDm 0.125 m | 1 | ZDIVO Z CDm | A | 1302HWa0798456073 | m3 | Celá stěna | Stávající | Zednické práce | ZDIVO Z CDm | yes | 1302Stě0798456074 | m3 | Stěna | 0 | 0.125 | 0.645 | 0.645 | 0.081 | 0.21 | 0.081 | 0.026 | 3.07
ZDIVO Z CDm | Půdorys 1.PP | ZDIVO Z CDm 0.125 m | 1 | ZDIVO Z CDm | A | 1302HWa0798456063 | m3 | Celá stěna | Stávající | Zednické práce | ZDIVO Z CDm | yes | 1302Stě0798456064 | m3 | Stěna | 0 | 0.125 | 0.384 | 0.384 | 0.048 | 0.125 | 0.048 | 0.016 | 3.07
ZDIVO Z CDm | Půdorys 1.PP | ZDIVO Z CDm 0.125 m | 1 | ZDIVO Z CDm | A | 1302HWa0798456085 | m3 | Celá stěna | Stávající | Zednické práce | ZDIVO Z CDm | yes | 1302Stě0798456086 | m3 | Stěna | 0 | 0.125 | 0.384 | 0.384 | 0.048 | 0.125 | 0.048 | 0.016 | 3.07
ZDIVO Z CDm | Půdorys 1.PP | ZDIVO Z CDm 0.125 m | 1 | ZDIVO Z CDm | A | 1302HWa0798456147 | m3 | Celá stěna | Stávající | Zednické práce | ZDIVO Z CDm | yes | 1302Stě0798456148 | m3 | Stěna | 0 | 0.125 | 3.254 | 3.254 | 0.407 | 1.06 | 0.407 | 0.132 | 3.07
ZDIVO Z CDm | Půdorys 1.PP | ZDIVO Z CDm 0.125 m | 1 | ZDIVO Z CDm | A | 1302HWa0798456157 | m3 | Celá stěna | Stávající | Zednické práce | ZDIVO Z CDm | yes | 1302Stě0798456159 | m3 | Stěna | 0 | 0.125 | 2.778 | 2.778 | 0.347 | 0.905 | 0.347 | 0.113 | 3.07
ZDIVO Z CDm | Půdorys 1.PP | ZDIVO Z CDm 0.125 m | 1 | ZDIVO Z CDm | A | 1302HWa0798456230 | m3 | Celá stěna | Stávající | Zednické práce | ZDIVO Z CDm | yes | 1302Stě0798456231 | m3 | Stěna | 0 | 0.125 | 0.614 | 0.614 | 0.077 | 0.2 | 0.077 | 0.025 | 3.07
ZDIVO Z CDm | Půdorys 1.PP | ZDIVO Z CDm 0.125 m | 1 | ZDIVO Z CDm | A | 1302HWa0798456240 | m3 | Celá stěna | Stávající | Zednické práce | ZDIVO Z CDm | yes | 1302Stě0798456241 | m3 | Stěna | 0 | 0.125 | 3.07 | 3.07 | 0.384 | 1 | 0.384 | 0.125 | 3.07
ZELEZOBETONOVÁ KCE | Půdorys 1.PP | ZELEZOBETONOVÁ KCE 0.25 m, LIGNOPOR 0.025 m, PÓROBETONOVÉ ZDIVO 0.08 m | 1 | ZELEZOBETONOVÁ KCE | A | 1302HWa0000000375 | m3 | Celá stěna | Stávající | Betonářské práce | ZELEZOBETONOVÁ KCE |  | 1302Stě0000000383 | m3 | Stěna | 0 | 0.355 | 110.036 | 110.036 | 33.027 | 26.738 | 33.027 | 9.458 | 4.1 | NEMSOK - Object Layer Attributes #2, 2D interakce: yes; Object Layer Attributes #2, Status: Stávající; Object Layer Attributes #2, Práce: Zateplovací systémy; Object Layer Attributes #2, Materiál: LIGNOPOR; Object Layer Attributes #2, Allright_Stavebni_dil_ID: 1302Stě0000000416; Object Layer Attributes #2, Jednotka: m2; Object Layer Attributes #2, Název_objektu: Stěna; Object Layer Attributes #3, 2D interakce: yes; Object Layer Attributes #3, Status: Stávající; Object Layer Attributes #3, Práce: Zednické práce; Object Layer Attributes #3, Materiál: PÓROBETONOVÉ ZDIVO; Object Layer Attributes #3, Allright_Stavebni_dil_ID: 1302Stě0000000414; Object Layer Attributes #3, Jednotka: m2; Object Layer Attributes #3, Název_objektu: Stěna; Pset_WallCommon - LoadBearing: yes
ZELEZOBETONOVÁ KCE | Půdorys 1.PP | ZELEZOBETONOVÁ KCE 0.25 m, LIGNOPOR 0.025 m, PÓROBETONOVÉ ZDIVO 0.08 m | 1 | ZELEZOBETONOVÁ KCE | A | 1302HWa0000000412 | m3 | Celá stěna | Stávající | Betonářské práce | ZELEZOBETONOVÁ KCE |  | 1302Stě0000000461 | m3 | Stěna | 0 | 0.355 | 26.633 | 23.563 | 8.61 | 5.9 | 7.781 | 2.498 | 4.1 | NEMSOK - Object Layer Attributes #2, 2D interakce: yes; Object Layer Attributes #2, Status: Stávající; Object Layer Attributes #2, Práce: Zateplovací systémy; Object Layer Attributes #2, Materiál: LIGNOPOR; Object Layer Attributes #2, Allright_Stavebni_dil_ID: 1302Stě0000000459; Object Layer Attributes #2, Jednotka: m2; Object Layer Attributes #2, Název_objektu: Stěna; Object Layer Attributes #3, 2D interakce: yes; Object Layer Attributes #3, Status: Stávající; Object Layer Attributes #3, Práce: Zednické práce; Object Layer Attributes #3, Materiál: PÓROBETONOVÉ ZDIVO; Object Layer Attributes #3, Allright_Stavebni_dil_ID: 1302Stě0000000457; Object Layer Attributes #3, Jednotka: m2; Object Layer Attributes #3, Název_objektu: Stěna; Pset_WallCommon - LoadBearing: yes
ZDIVO Z CDm | Půdorys 1.PP | ZDIVO Z CDm 0.125 m | 1 | ZDIVO Z CDm | A | 1302HWa0798456356 | m3 | Celá stěna | Stávající | Zednické práce | ZDIVO Z CDm | yes | 1302Stě0798456357 | m3 | Stěna | 0 | 0.125 | 5.833 | 5.833 | 0.729 | 1.9 | 0.729 | 0.237 | 3.07
ZDIVO Z CDm | Půdorys 1.PP | ZDIVO Z CDm 0.125 m | 1 | ZDIVO Z CDm | A | 1302HWa0798456370 | m3 | Celá stěna | Stávající | Zednické práce | ZDIVO Z CDm | yes | 1302Stě0798456371 | m3 | Stěna | 0 | 0.125 | 4.59 | 4.59 | 0.574 | 1.495 | 0.574 | 0.187 | 3.07
YTONG 125 | Půdorys 1.NP | YTONG 125 0.125 m |  | YTONG 125 | EI 180 | 1402HWa0000000337 | m3 | Celá stěna | Stávající | Zednické práce | YTONG 125 |  | 1402Stě0000000338 | m2 | Stěna | 0.926 | 0.125 | 10.72 | 10.72 | 1.34 | 3.2 | 1.34 | 0.4 | 3.35 | Pset_WallCommon - AcousticRating: 39 dB
ZELEZOBETONOVÁ KCE | Půdorys 1.NP | ZELEZOBETONOVÁ KCE 0.25 m, MINERÁLNÍ VATA 0.12 m | 1 | ZELEZOBETONOVÁ KCE | A | 1402HWa0798441289 | m3 | Celá stěna | Stávající | Betonářské práce | ZELEZOBETONOVÁ KCE | no | 1402Stě0798441290 | m3 | Stěna | 0 | 0.37 | 11.88 | 8.64 | 4.306 | 3.24 | 3.107 | 1.207 | 3.6 | NEMSOK - Object Layer Attributes #2, 2D interakce: yes; Object Layer Attributes #2, Status: Stávající; Object Layer Attributes #2, Práce: Zateplovací systémy; Object Layer Attributes #2, Materiál: MINERÁLNÍ VATA; Object Layer Attributes #2, Allright_Stavebni_dil_ID: 1402Stě0798441291; Object Layer Attributes #2, Jednotka: m2; Object Layer Attributes #2, Název_objektu: Stěna; Object Layer Attributes #2, Staticky nosná konstrukce: no
ZELEZOBETONOVÁ KCE | Půdorys 1.NP | MINERÁLNÍ VATA 0.12 m | 1 | ZELEZOBETONOVÁ KCE | A | 1402HWa0798441408 | m3 | Celá stěna | Stávající | Zateplovací systémy | MINERÁLNÍ VATA | no | 1402Stě0798441410 | m2 | Stěna | 0 | 0.12 | 0.595 | 0.595 | 0.071 | 0.17 | 0.071 | 0.02 | 3.5
ZDIVO Z CDm | Půdorys 1.NP | ZDIVO Z CDm 0.125 m | 1 | ZDIVO Z CDm | A | 1402HWa0000000067 | m3 | Celá stěna | Stávající | Zednické práce | ZDIVO Z CDm | yes | 1402Stě0000000068 | m3 | Stěna | 0 | 0.125 | 13.902 | 11.479 | 1.738 | 4.15 | 1.435 | 0.519 | 3.35
ZDIVO Z CDm | Půdorys 1.NP | ZDIVO Z CDm 0.125 m | 1 | ZDIVO Z CDm | A | 1402HWa0000000058 | m3 | Celá stěna | Stávající | Zednické práce | ZDIVO Z CDm | yes | 1402Stě0000000059 | m3 | Stěna | 0 | 0.125 | 13.902 | 13.903 | 1.738 | 4.15 | 1.738 | 0.519 | 3.35
ZELEZOBETONOVÁ KCE | Půdorys 1.NP | ZELEZOBETONOVÁ KCE 0.25 m | 1 | ZELEZOBETONOVÁ KCE | A | 1402HWa0798441297 | m3 | Celá stěna | Stávající | Betonářské práce | ZELEZOBETONOVÁ KCE |  | 1402Stě0798441298 | m3 | Stěna | 0 | 0.25 | 39.96 | 36.264 | 9.99 | 11.1 | 9.066 | 2.775 | 3.6
PÓROBETONOVÉ ZDIVO | Půdorys 1.NP | PÓROBETONOVÉ ZDIVO 0.1 m |  | PÓROBETONOVÉ ZDIVO | EI 120 | 1402HWa0798451997 | m3 | Celá stěna | Stávající | Zednické práce | PÓROBETONOVÉ ZDIVO |  | 1402Stě0798451998 | m2 | Stěna | 1.111 | 0.1 | 10.72 | 10.72 | 1.072 | 3.2 | 1.072 | 0.32 | 3.35 | Pset_WallCommon - AcousticRating: 37 dB
PÓROBETONOVÉ ZDIVO | Půdorys 1.NP | PÓROBETONOVÉ ZDIVO 0.1 m |  | PÓROBETONOVÉ ZDIVO | EI 120 | 1402HWa0798453315 | m3 | Celá stěna | Stávající | Zednické práce | PÓROBETONOVÉ ZDIVO |  | 1402Stě0798453311 | m2 | Stěna | 1.111 | 0.1 | 10.72 | 7.21 | 1.072 | 3.2 | 0.721 | 0.32 | 3.35 | Pset_WallCommon - AcousticRating: 37 dB
YTONG 150 | Půdorys 1.NP | YTONG 150 0.15 m |  | YTONG 150 | EI 180 | 1402HWa0000000195 | m3 | Celá stěna | Stávající | Zednické práce | YTONG 150 |  | 1402Stě0000000196 | m2 | Stěna | 0.794 | 0.15 | 39.362 | 32.323 | 5.904 | 11.75 | 4.848 | 1.763 | 3.35 | Pset_WallCommon - AcousticRating: 41 dB
ZELEZOBETONOVÁ KCE | Půdorys 1.NP | ZELEZOBETONOVÁ KCE 0.2 m | 1 | ZELEZOBETONOVÁ KCE | A | 1402HWa0000000282 | m3 | Celá stěna | Stávající | Betonářské práce | ZELEZOBETONOVÁ KCE |  | 1402Stě0000000283 | m3 | Stěna | 0 | 0.2 | 10.72 | 10.72 | 2.144 | 3.2 | 2.144 | 0.64 | 3.35
ZELEZOBETONOVÁ KCE | Půdorys 1.NP | MINERÁLNÍ VATA 0.12 m | 1 | ZELEZOBETONOVÁ KCE | A | 1402HWa0798441355 | m3 | Celá stěna | Stávající | Zateplovací systémy | MINERÁLNÍ VATA | no | 1402Stě0798441357 | m2 | Stěna | 0 | 0.12 | 0.595 | 0.595 | 0.071 | 0.17 | 0.071 | 0.02 | 3.5
ZDIVO Z CDm | Půdorys 1.NP | ZDIVO Z CDm 0.125 m | 1 | ZDIVO Z CDm | A | 1402HWa0798438672 | m3 | Celá stěna | Stávající | Zednické práce | ZDIVO Z CDm | yes | 1402Stě0798438677 | m3 | Stěna | 0 | 0.125 | 1.742 | 1.742 | 0.218 | 0.52 | 0.218 | 0.065 | 3.35
ZELEZOBETONOVÁ KCE | Půdorys 1.NP | ZELEZOBETONOVÁ KCE 0.3 m, MINERÁLNÍ VATA 0.12 m | 1 | ZELEZOBETONOVÁ KCE | A | 1402HWa0798438675 | m3 | Celá stěna | Stávající | Betonářské práce | ZELEZOBETONOVÁ KCE | no | 1402Stě0798438694 | m3 | Stěna | 0 | 0.42 | 3.99 | 3.99 | 1.58 | 1.08 | 1.58 | 0.443 | 3.6 | NEMSOK - Object Layer Attributes #2, 2D interakce: yes; Object Layer Attributes #2, Status: Stávající; Object Layer Attributes #2, Práce: Zateplovací systémy; Object Layer Attributes #2, Materiál: MINERÁLNÍ VATA; Object Layer Attributes #2, Allright_Stavebni_dil_ID: 1402Stě0798438685; Object Layer Attributes #2, Jednotka: m2; Object Layer Attributes #2, Název_objektu: Stěna; Object Layer Attributes #2, Staticky nosná konstrukce: no
ZELEZOBETONOVÁ KCE | Půdorys 1.NP | MINERÁLNÍ VATA 0.12 m | 1 | ZELEZOBETONOVÁ KCE | A | 1402HWa0798438682 | m3 | Celá stěna | Stávající | Zateplovací systémy | MINERÁLNÍ VATA | no | 1402Stě0798438695 | m2 | Stěna | 0 | 0.12 | 0.595 | 0.595 | 0.071 | 0.17 | 0.071 | 0.02 | 3.5
ZELEZOBETONOVÁ KCE | Půdorys 1.NP | ZELEZOBETONOVÁ KCE 0.2 m | 1 | ZELEZOBETONOVÁ KCE | A | 1402HWa0000000273 | m3 | Celá stěna | Stávající | Betonářské práce | ZELEZOBETONOVÁ KCE |  | 1402Stě0000000275 | m3 | Stěna | 0 | 0.2 | 18.09 | 18.09 | 3.618 | 5.4 | 3.618 | 1.08 | 3.35
ZELEZOBETONOVÁ KCE | Půdorys 1.NP | ZELEZOBETONOVÁ KCE 0.25 m, MINERÁLNÍ VATA 0.12 m |  | ZELEZOBETONOVÁ KCE | A | 1402HWa0798438674 | m3 | Celá stěna | Stávající | Betonářské práce | ZELEZOBETONOVÁ KCE | no | 1402Stě0798438788 | m3 | Stěna | 0 | 0.37 | 129.6 | 97.2 | 47.419 | 35.88 | 35.431 | 13.291 | 3.6 | NEMSOK - Object Layer Attributes #2, 2D interakce: yes; Object Layer Attributes #2, Status: Stávající; Object Layer Attributes #2, Práce: Zateplovací systémy; Object Layer Attributes #2, Materiál: MINERÁLNÍ VATA; Object Layer Attributes #2, Allright_Stavebni_dil_ID: 1402Stě0798438787; Object Layer Attributes #2, Jednotka: m2; Object Layer Attributes #2, Název_objektu: Stěna; Object Layer Attributes #2, Staticky nosná konstrukce: no
ZDIVO Z CDm | Půdorys 1.NP | ZDIVO Z CDm 0.125 m | 1 | ZDIVO Z CDm | A | 1402HWa0798441305 | m3 | Celá stěna | Stávající | Zednické práce | ZDIVO Z CDm | yes | 1402Stě0798441306 | m3 | Stěna | 0 | 0.125 | 5.192 | 5.193 | 0.649 | 1.55 | 0.649 | 0.194 | 3.35
ZELEZOBETONOVÁ KCE | Půdorys 1.NP | ZELEZOBETONOVÁ KCE 0.2 m | 1 | ZELEZOBETONOVÁ KCE | A | 1402HWa0000000182 | m3 | Celá stěna | Stávající | Betonářské práce | ZELEZOBETONOVÁ KCE |  | 1402Stě0000000183 | m3 | Stěna | 0 | 0.2 | 18.09 | 14.68 | 3.618 | 5.4 | 2.936 | 1.08 | 3.35
PÓROBETONOVÉ ZDIVO | Půdorys 1.NP | PÓROBETONOVÉ ZDIVO 0.1 m |  | PÓROBETONOVÉ ZDIVO | EI 120 | 1402HWa0798453156 | m3 | Celá stěna | Stávající | Zednické práce | PÓROBETONOVÉ ZDIVO |  | 1402Stě0798453160 | m2 | Stěna | 1.111 | 0.1 | 10.72 | 7.21 | 1.072 | 3.2 | 0.721 | 0.32 | 3.35 | Pset_WallCommon - AcousticRating: 37 dB
PÓROBETONOVÉ ZDIVO | Půdorys 1.NP | PÓROBETONOVÉ ZDIVO 0.1 m |  | PÓROBETONOVÉ ZDIVO | EI 120 | 1402HWa0798452996 | m3 | Celá stěna | Stávající | Zednické práce | PÓROBETONOVÉ ZDIVO |  | 1402Stě0798453000 | m2 | Stěna | 1.111 | 0.1 | 10.72 | 7.21 | 1.072 | 3.2 | 0.721 | 0.32 | 3.35 | Pset_WallCommon - AcousticRating: 37 dB
PÓROBETONOVÉ ZDIVO | Půdorys 1.NP | PÓROBETONOVÉ ZDIVO 0.1 m |  | PÓROBETONOVÉ ZDIVO | EI 120 | 1402HWa0798452926 | m3 | Celá stěna | Stávající | Zednické práce | PÓROBETONOVÉ ZDIVO |  | 1402Stě0798452930 | m2 | Stěna | 1.111 | 0.1 | 10.72 | 7.21 | 1.072 | 3.2 | 0.721 | 0.32 | 3.35 | Pset_WallCommon - AcousticRating: 37 dB
PÓROBETONOVÉ ZDIVO | Půdorys 1.NP | PÓROBETONOVÉ ZDIVO 0.1 m |  | PÓROBETONOVÉ ZDIVO | EI 120 | 1402HWa0798453078 | m3 | Celá stěna | Stávající | Zednické práce | PÓROBETONOVÉ ZDIVO |  | 1402Stě0798453082 | m2 | Stěna | 1.111 | 0.1 | 10.72 | 7.21 | 1.072 | 3.2 | 0.721 | 0.32 | 3.35 | Pset_WallCommon - AcousticRating: 37 dB
PÓROBETONOVÉ ZDIVO | Půdorys 1.NP | PÓROBETONOVÉ ZDIVO 0.1 m |  | PÓROBETONOVÉ ZDIVO | EI 120 | 1402HWa0798453244 | m3 | Celá stěna | Stávající | Zednické práce | PÓROBETONOVÉ ZDIVO |  | 1402Stě0798453248 | m2 | Stěna | 1.111 | 0.1 | 10.72 | 7.21 | 1.072 | 3.2 | 0.721 | 0.32 | 3.35 | Pset_WallCommon - AcousticRating: 37 dB
PÓROBETONOVÉ ZDIVO | Půdorys 1.NP | PÓROBETONOVÉ ZDIVO 0.1 m |  | PÓROBETONOVÉ ZDIVO | EI 120 | 1402HWa0798453196 | m3 | Celá stěna | Stávající | Zednické práce | PÓROBETONOVÉ ZDIVO |  | 1402Stě0798453200 | m2 | Stěna | 1.111 | 0.1 | 10.72 | 7.21 | 1.072 | 3.2 | 0.721 | 0.32 | 3.35 | Pset_WallCommon - AcousticRating: 37 dB
PÓROBETONOVÉ ZDIVO | Půdorys 1.NP | PÓROBETONOVÉ ZDIVO 0.1 m |  | PÓROBETONOVÉ ZDIVO | EI 120 | 1402HWa0798453040 | m3 | Celá stěna | Stávající | Zednické práce | PÓROBETONOVÉ ZDIVO |  | 1402Stě0798453044 | m2 | Stěna | 1.111 | 0.1 | 10.72 | 7.21 | 1.072 | 3.2 | 0.721 | 0.32 | 3.35 | Pset_WallCommon - AcousticRating: 37 dB
PÓROBETONOVÉ ZDIVO | Půdorys 1.NP | PÓROBETONOVÉ ZDIVO 0.1 m |  | PÓROBETONOVÉ ZDIVO | EI 120 | 1402HWa0798452894 | m3 | Celá stěna | Stávající | Zednické práce | PÓROBETONOVÉ ZDIVO |  | 1402Stě0798452899 | m2 | Stěna | 1.111 | 0.1 | 10.72 | 7.21 | 1.072 | 3.2 | 0.721 | 0.32 | 3.35 | Pset_WallCommon - AcousticRating: 37 dB
PÓROBETONOVÉ ZDIVO | Půdorys 1.NP | PÓROBETONOVÉ ZDIVO 0.1 m |  | PÓROBETONOVÉ ZDIVO | EI 120 | 1402HWa0798452962 | m3 | Celá stěna | Stávající | Zednické práce | PÓROBETONOVÉ ZDIVO |  | 1402Stě0798452966 | m2 | Stěna | 1.111 | 0.1 | 10.72 | 7.21 | 1.072 | 3.2 | 0.721 | 0.32 | 3.35 | Pset_WallCommon - AcousticRating: 37 dB
PÓROBETONOVÉ ZDIVO | Půdorys 1.NP | PÓROBETONOVÉ ZDIVO 0.1 m |  | PÓROBETONOVÉ ZDIVO | EI 120 | 1402HWa0798453116 | m3 | Celá stěna | Stávající | Zednické práce | PÓROBETONOVÉ ZDIVO |  | 1402Stě0798453120 | m2 | Stěna | 1.111 | 0.1 | 10.72 | 7.21 | 1.072 | 3.2 | 0.721 | 0.32 | 3.35 | Pset_WallCommon - AcousticRating: 37 dB
ZELEZOBETONOVÁ KCE | Půdorys 1.NP | ZELEZOBETONOVÁ KCE 0.3 m, MINERÁLNÍ VATA 0.12 m | 1 | ZELEZOBETONOVÁ KCE | A | 1402HWa0798441255 | m3 | Celá stěna | Stávající | Betonářské práce | ZELEZOBETONOVÁ KCE | no | 1402Stě0798441256 | m3 | Stěna | 0 | 0.42 | 2.87 | 2.87 | 1.1 | 0.76 | 1.1 | 0.308 | 3.6 | NEMSOK - Object Layer Attributes #2, 2D interakce: yes; Object Layer Attributes #2, Status: Stávající; Object Layer Attributes #2, Práce: Zateplovací systémy; Object Layer Attributes #2, Materiál: MINERÁLNÍ VATA; Object Layer Attributes #2, Allright_Stavebni_dil_ID: 1402Stě0798441257; Object Layer Attributes #2, Jednotka: m2; Object Layer Attributes #2, Název_objektu: Stěna; Object Layer Attributes #2, Staticky nosná konstrukce: no
ZELEZOBETONOVÁ KCE | Půdorys 1.NP | ZELEZOBETONOVÁ KCE 0.3 m, MINERÁLNÍ VATA 0.12 m | 1 | ZELEZOBETONOVÁ KCE | A | 1402HWa0798441317 | m3 | Celá stěna | Stávající | Betonářské práce | ZELEZOBETONOVÁ KCE | no | 1402Stě0798441318 | m3 | Stěna | 0 | 0.42 | 2.7 | 2.7 | 1.075 | 0.69 | 1.075 | 0.301 | 3.6 | NEMSOK - Object Layer Attributes #2, 2D interakce: yes; Object Layer Attributes #2, Status: Stávající; Object Layer Attributes #2, Práce: Zateplovací systémy; Object Layer Attributes #2, Materiál: MINERÁLNÍ VATA; Object Layer Attributes #2, Allright_Stavebni_dil_ID: 1402Stě0798441319; Object Layer Attributes #2, Jednotka: m2; Object Layer Attributes #2, Název_objektu: Stěna; Object Layer Attributes #2, Staticky nosná konstrukce: no
ZELEZOBETONOVÁ KCE | Půdorys 1.NP | ZELEZOBETONOVÁ KCE 0.3 m, MINERÁLNÍ VATA 0.12 m | 1 | ZELEZOBETONOVÁ KCE | A | 1402HWa0798441268 | m3 | Celá stěna | Stávající | Betonářské práce | ZELEZOBETONOVÁ KCE | no | 1402Stě0798441269 | m3 | Stěna | 0 | 0.42 | 4.5 | 4.5 | 1.875 | 1.25 | 1.875 | 0.525 | 3.6 | NEMSOK - Object Layer Attributes #2, 2D interakce: yes; Object Layer Attributes #2, Status: Stávající; Object Layer Attributes #2, Práce: Zateplovací systémy; Object Layer Attributes #2, Materiál: MINERÁLNÍ VATA; Object Layer Attributes #2, Allright_Stavebni_dil_ID: 1402Stě0798441270; Object Layer Attributes #2, Jednotka: m2; Object Layer Attributes #2, Název_objektu: Stěna; Object Layer Attributes #2, Staticky nosná konstrukce: no
ZELEZOBETONOVÁ KCE | Půdorys 1.NP | ZELEZOBETONOVÁ KCE 0.2 m | 1 | ZELEZOBETONOVÁ KCE | A | 1402HWa0000000309 | m3 | Celá stěna | Stávající | Betonářské práce | ZELEZOBETONOVÁ KCE |  | 1402Stě0000000310 | m3 | Stěna | 0 | 0.2 | 10.72 | 10.72 | 2.144 | 3.2 | 2.144 | 0.64 | 3.35
ZELEZOBETONOVÁ KCE | Půdorys 1.NP | ZELEZOBETONOVÁ KCE 0.2 m | 1 | ZELEZOBETONOVÁ KCE | A | 1402HWa0000000291 | m3 | Celá stěna | Stávající | Betonářské práce | ZELEZOBETONOVÁ KCE |  | 1402Stě0000000293 | m3 | Stěna | 0 | 0.2 | 18.09 | 18.09 | 3.618 | 5.4 | 3.618 | 1.08 | 3.35
PÓROBETONOVÉ ZDIVO | Půdorys 1.NP | PÓROBETONOVÉ ZDIVO 0.1 m | 1 | PÓROBETONOVÉ ZDIVO | EI 120 | 1402HWa0798440302 | m3 | Celá stěna | Stávající | Zednické práce | PÓROBETONOVÉ ZDIVO |  | 1402Stě0798440303 | m2 | Stěna | 1.111 | 0.1 | 17.671 | 17.671 | 1.767 | 5.275 | 1.767 | 0.527 | 3.35 | Pset_WallCommon - AcousticRating: 37 dB
ZELEZOBETONOVÁ KCE | Půdorys 1.NP | ZELEZOBETONOVÁ KCE 0.2 m | 1 | ZELEZOBETONOVÁ KCE | A | 1402HWa0000000294 | m3 | Celá stěna | Stávající | Betonářské práce | ZELEZOBETONOVÁ KCE |  | 1402Stě0000000296 | m3 | Stěna | 0 | 0.2 | 18.09 | 18.09 | 3.618 | 5.4 | 3.618 | 1.08 | 3.35
ZDIVO Z CDm | Půdorys 1.NP | ZDIVO Z CDm 0.125 m | 1 | ZDIVO Z CDm | A | 1402HWa0000000512 | m3 | Celá stěna | Stávající | Zednické práce | ZDIVO Z CDm | yes | 1402Stě0000000513 | m3 | Stěna | 0 | 0.125 | 1.742 | 1.742 | 0.218 | 0.52 | 0.218 | 0.065 | 3.35
ZELEZOBETONOVÁ KCE | Půdorys 1.NP | ZELEZOBETONOVÁ KCE 0.3 m, MINERÁLNÍ VATA 0.12 m | 1 | ZELEZOBETONOVÁ KCE | A | 1402HWa0000000443 | m3 | Celá stěna | Stávající | Betonářské práce | ZELEZOBETONOVÁ KCE | no | 1402Stě0000000444 | m3 | Stěna | 0 | 0.42 | 3.99 | 3.99 | 1.58 | 1.08 | 1.58 | 0.443 | 3.6 | NEMSOK - Object Layer Attributes #2, 2D interakce: yes; Object Layer Attributes #2, Status: Stávající; Object Layer Attributes #2, Práce: Zateplovací systémy; Object Layer Attributes #2, Materiál: MINERÁLNÍ VATA; Object Layer Attributes #2, Allright_Stavebni_dil_ID: 1402Stě0000000601; Object Layer Attributes #2, Jednotka: m2; Object Layer Attributes #2, Název_objektu: Stěna; Object Layer Attributes #2, Staticky nosná konstrukce: no
ZELEZOBETONOVÁ KCE | Půdorys 1.NP | MINERÁLNÍ VATA 0.12 m | 1 | ZELEZOBETONOVÁ KCE | A | 1402HWa0000000702 | m3 | Celá stěna | Stávající | Zateplovací systémy | MINERÁLNÍ VATA | no | 1402Stě0000000703 | m2 | Stěna | 0 | 0.12 | 0.595 | 0.595 | 0.071 | 0.17 | 0.071 | 0.02 | 3.5
ZDIVO Z CDm | Půdorys 1.NP | ZDIVO Z CDm 0.125 m | 1 | ZDIVO Z CDm | A | 1402HWa0798450304 | m3 | Celá stěna | Stávající | Zednické práce | ZDIVO Z CDm | yes | 1402Stě0798450306 | m3 | Stěna | 0 | 0.125 | 5.192 | 5.193 | 0.649 | 1.55 | 0.649 | 0.194 | 3.35
PÓROBETONOVÉ ZDIVO | Půdorys 1.NP | PÓROBETONOVÉ ZDIVO 0.1 m |  | PÓROBETONOVÉ ZDIVO | EI 120 | 1402HWa0798452443 | m3 | Celá stěna | Stávající | Zednické práce | PÓROBETONOVÉ ZDIVO |  | 1402Stě0798452447 | m2 | Stěna | 1.111 | 0.1 | 10.72 | 7.21 | 1.072 | 3.2 | 0.721 | 0.32 | 3.35 | Pset_WallCommon - AcousticRating: 37 dB
PÓROBETONOVÉ ZDIVO | Půdorys 1.NP | PÓROBETONOVÉ ZDIVO 0.1 m |  | PÓROBETONOVÉ ZDIVO | EI 120 | 1402HWa0798452517 | m3 | Celá stěna | Stávající | Zednické práce | PÓROBETONOVÉ ZDIVO |  | 1402Stě0798452521 | m2 | Stěna | 1.111 | 0.1 | 10.72 | 7.21 | 1.072 | 3.2 | 0.721 | 0.32 | 3.35 | Pset_WallCommon - AcousticRating: 37 dB
PÓROBETONOVÉ ZDIVO | Půdorys 1.NP | PÓROBETONOVÉ ZDIVO 0.1 m |  | PÓROBETONOVÉ ZDIVO | EI 120 | 1402HWa0798452689 | m3 | Celá stěna | Stávající | Zednické práce | PÓROBETONOVÉ ZDIVO |  | 1402Stě0798452693 | m2 | Stěna | 1.111 | 0.1 | 10.72 | 7.86 | 1.072 | 3.2 | 0.786 | 0.32 | 3.35 | Pset_WallCommon - AcousticRating: 37 dB
PÓROBETONOVÉ ZDIVO | Půdorys 1.NP | PÓROBETONOVÉ ZDIVO 0.1 m |  | PÓROBETONOVÉ ZDIVO | EI 120 | 1402HWa0798452647 | m3 | Celá stěna | Stávající | Zednické práce | PÓROBETONOVÉ ZDIVO |  | 1402Stě0798452651 | m2 | Stěna | 1.111 | 0.1 | 10.72 | 10.72 | 1.072 | 3.2 | 1.072 | 0.32 | 3.35 | Pset_WallCommon - AcousticRating: 37 dB
PÓROBETONOVÉ ZDIVO | Půdorys 1.NP | PÓROBETONOVÉ ZDIVO 0.1 m |  | PÓROBETONOVÉ ZDIVO | EI 120 | 1402HWa0798452477 | m3 | Celá stěna | Stávající | Zednické práce | PÓROBETONOVÉ ZDIVO |  | 1402Stě0798452481 | m2 | Stěna | 1.111 | 0.1 | 10.72 | 7.21 | 1.072 | 3.2 | 0.721 | 0.32 | 3.35 | Pset_WallCommon - AcousticRating: 37 dB
PÓROBETONOVÉ ZDIVO | Půdorys 1.NP | PÓROBETONOVÉ ZDIVO 0.1 m |  | PÓROBETONOVÉ ZDIVO | EI 120 | 1402HWa0798452559 | m3 | Celá stěna | Stávající | Zednické práce | PÓROBETONOVÉ ZDIVO |  | 1402Stě0798452563 | m2 | Stěna | 1.111 | 0.1 | 10.72 | 7.21 | 1.072 | 3.2 | 0.721 | 0.32 | 3.35 | Pset_WallCommon - AcousticRating: 37 dB
PÓROBETONOVÉ ZDIVO | Půdorys 1.NP | PÓROBETONOVÉ ZDIVO 0.1 m |  | PÓROBETONOVÉ ZDIVO | EI 120 | 1402HWa0798452363 | m3 | Celá stěna | Stávající | Zednické práce | PÓROBETONOVÉ ZDIVO |  | 1402Stě0798452367 | m2 | Stěna | 1.111 | 0.1 | 10.72 | 7.21 | 1.072 | 3.2 | 0.721 | 0.32 | 3.35 | Pset_WallCommon - AcousticRating: 37 dB
PÓROBETONOVÉ ZDIVO | Půdorys 1.NP | PÓROBETONOVÉ ZDIVO 0.1 m |  | PÓROBETONOVÉ ZDIVO | EI 120 | 1402HWa0798440270 | m3 | Celá stěna | Stávající | Zednické práce | PÓROBETONOVÉ ZDIVO |  | 1402Stě0798440282 | m2 | Stěna | 1.111 | 0.1 | 10.72 | 7.21 | 1.072 | 3.2 | 0.721 | 0.32 | 3.35 | Pset_WallCommon - AcousticRating: 37 dB
PÓROBETONOVÉ ZDIVO | Půdorys 1.NP | PÓROBETONOVÉ ZDIVO 0.1 m |  | PÓROBETONOVÉ ZDIVO | EI 120 | 1402HWa0798452407 | m3 | Celá stěna | Stávající | Zednické práce | PÓROBETONOVÉ ZDIVO |  | 1402Stě0798452411 | m2 | Stěna | 1.111 | 0.1 | 10.72 | 7.21 | 1.072 | 3.2 | 0.721 | 0.32 | 3.35 | Pset_WallCommon - AcousticRating: 37 dB
ZDIVO Z CDm | Půdorys 1.NP | ZDIVO Z CDm 0.125 m | 1 | ZDIVO Z CDm | A | 1402HWa0798453573 | m3 | Celá stěna | Stávající | Zednické práce | ZDIVO Z CDm |  | 1402Stě0798453574 | m3 | Stěna | 0 | 0.125 | 17.671 | 17.671 | 2.209 | 5.275 | 2.209 | 0.659 | 3.35
ZDIVO Z CDm | Půdorys 1.NP | ZDIVO Z CDm 0.125 m | 1 | ZDIVO Z CDm | A | 1402HWa0798453597 | m3 | Celá stěna | Stávající | Zednické práce | ZDIVO Z CDm | yes | 1402Stě0798453599 | m3 | Stěna | 0 | 0.125 | 24.455 | 16.577 | 3.057 | 7.3 | 2.072 | 0.913 | 3.35
ZDIVO Z CDm | Půdorys 1.NP | ZDIVO Z CDm 0.125 m | 1 | ZDIVO Z CDm | A | 1402HWa0798453694 | m3 | Celá stěna | Stávající | Zednické práce | ZDIVO Z CDm | yes | 1402Stě0798453695 | m3 | Stěna | 0 | 0.125 | 9.715 | 9.715 | 1.214 | 2.9 | 1.214 | 0.363 | 3.35
ZDIVO Z CDm | Půdorys 1.NP | ZDIVO Z CDm 0.125 m | 1 | ZDIVO Z CDm | A | 1402HWa0798453701 | m3 | Celá stěna | Stávající | Zednické práce | ZDIVO Z CDm | yes | 1402Stě0798453702 | m3 | Stěna | 0 | 0.125 | 11.474 | 11.474 | 1.434 | 3.425 | 1.434 | 0.428 | 3.35
ZDIVO Z CDm | Půdorys 1.NP | ZDIVO Z CDm 0.125 m | 1 | ZDIVO Z CDm | A | 1402HWa0798453745 | m3 | Celá stěna | Stávající | Zednické práce | ZDIVO Z CDm | yes | 1402Stě0798453746 | m3 | Stěna | 0 | 0.125 | 5.695 | 5.695 | 0.712 | 1.7 | 0.712 | 0.212 | 3.35
ZELEZOBETONOVÁ KCE | Půdorys 1.NP | ZELEZOBETONOVÁ KCE 0.3 m | 1 | ZELEZOBETONOVÁ KCE | A | 1402HWa0798441520 | m3 | Celá stěna | Stávající | Betonářské práce | ZELEZOBETONOVÁ KCE |  | 1402Stě0798441521 | m3 | Stěna | 0 | 0.3 | 2.7 | 2.7 | 0.81 | 0.75 | 0.81 | 0.225 | 3.6
ZDIVO Z CDm | Půdorys 1.NP | ZDIVO Z CDm 0.125 m | 1 | ZDIVO Z CDm | A | 1402HWa0798453757 | m3 | Celá stěna | Stávající | Zednické práce | ZDIVO Z CDm | yes | 1402Stě0798453758 | m3 | Stěna | 0 | 0.125 | 7.035 | 7.035 | 0.879 | 2.1 | 0.879 | 0.262 | 3.35
ZDIVO Z CDm | Půdorys 1.NP | ZDIVO Z CDm 0.125 m | 1 | ZDIVO Z CDm | A | 1402HWa0798453930 | m3 | Celá stěna | Stávající | Zednické práce | ZDIVO Z CDm | yes | 1402Stě0798453931 | m3 | Stěna | 0 | 0.125 | 5.025 | 3.611 | 0.628 | 1.5 | 0.451 | 0.188 | 3.35
ZDIVO Z CDm | Půdorys 1.NP | ZDIVO Z CDm 0.125 m | 1 | ZDIVO Z CDm | A | 1402HWa0798453915 | m3 | Celá stěna | Stávající | Zednické práce | ZDIVO Z CDm | yes | 1402Stě0798453916 | m3 | Stěna | 0 | 0.125 | 6.867 | 7.035 | 0.858 | 2.05 | 0.858 | 0.256 | 3.35
ZDIVO Z CDm | Půdorys 1.NP | ZDIVO Z CDm 0.125 m | 1 | ZDIVO Z CDm | A | 1402HWa0798455133 | m3 | Celá stěna | Stávající | Zednické práce | ZDIVO Z CDm |  | 1402Stě0798455135 | m3 | Stěna | 0 | 0.125 | 11.641 | 9.823 | 1.455 | 3.475 | 1.228 | 0.434 | 3.35
SDK SVISLA CAST PODHLEDU | Půdorys 1.NP | SDK SVISLA CAST PODHLEDU 0.04 m | 1 | SDK SVISLA CAST PODHLEDU |  | 1402HWa0798455188 | m3 | Celá stěna | Stávající | Suché stavební práce | SDK SVISLA CAST PODHLEDU |  | 1402Stě0798455189 | m2 | Stěna |  | 0.04 | 3.06 | 3.06 | 0.122 | 6.8 | 0.122 | 0.272 | 0.45
ZDIVO Z CDm | Půdorys 1.NP | ZDIVO Z CDm 0.125 m | 1 | ZDIVO Z CDm | A | 1402HWa0798454058 | m3 | Celá stěna | Stávající | Zednické práce | ZDIVO Z CDm | yes | 1402Stě0798454059 | m3 | Stěna | 0 | 0.125 | 8.794 | 8.794 | 1.099 | 2.625 | 1.099 | 0.328 | 3.35
ZDIVO Z CDm | Půdorys 1.NP | ZDIVO Z CDm 0.125 m | 1 | ZDIVO Z CDm | A | 1402HWa0798454073 | m3 | Celá stěna | Stávající | Zednické práce | ZDIVO Z CDm | yes | 1402Stě0798454092 | m3 | Stěna | 0 | 0.125 | 14.656 | 12.838 | 1.832 | 4.375 | 1.605 | 0.547 | 3.35
ZDIVO Z CDm | Půdorys 1.NP | ZDIVO Z CDm 0.125 m | 1 | ZDIVO Z CDm | A | 1402HWa0798454119 | m3 | Celá stěna | Stávající | Zednické práce | ZDIVO Z CDm | yes | 1402Stě0798454120 | m3 | Stěna | 0 | 0.125 | 1.256 | 1.256 | 0.157 | 0.375 | 0.157 | 0.047 | 3.35
ZDIVO Z CDm | Půdorys 1.NP | ZDIVO Z CDm 0.125 m | 1 | ZDIVO Z CDm | A | 1402HWa0798453689 | m3 | Celá stěna | Stávající | Zednické práce | ZDIVO Z CDm | yes | 1402Stě0798453690 | m3 | Stěna | 0 | 0.125 | 18.844 | 15.612 | 2.355 | 5.625 | 1.951 | 0.703 | 3.35
ZDIVO Z CDm | Půdorys 1.NP | ZDIVO Z CDm 0.125 m | 1 | ZDIVO Z CDm | A | 1402HWa0000000318 | m3 | Celá stěna | Stávající | Zednické práce | ZDIVO Z CDm | yes | 1402Stě0000000319 | m3 | Stěna | 0 | 0.125 | 1.591 | 1.591 | 0.199 | 0.475 | 0.199 | 0.059 | 3.35
ZDIVO Z CDm | Půdorys 1.NP | ZDIVO Z CDm 0.125 m | 1 | ZDIVO Z CDm | A | 1402HWa0798454141 | m3 | Celá stěna | Stávající | Zednické práce | ZDIVO Z CDm | yes | 1402Stě0798454142 | m3 | Stěna | 0 | 0.125 | 1.256 | 1.256 | 0.157 | 0.375 | 0.157 | 0.047 | 3.35
ZDIVO Z CDm | Půdorys 1.NP | ZDIVO Z CDm 0.125 m | 1 | ZDIVO Z CDm | A | 1402HWa0798454153 | m3 | Celá stěna | Stávající | Zednické práce | ZDIVO Z CDm | yes | 1402Stě0798454155 | m3 | Stěna | 0 | 0.125 | 2.01 | 2.01 | 0.251 | 0.6 | 0.251 | 0.075 | 3.35
YTONG 150 | Půdorys 1.NP | YTONG 150 0.15 m |  | YTONG 150 | EI 180 | 1402HWa0000000204 | m3 | Celá stěna | Stávající | Zednické práce | YTONG 150 |  | 1402Stě0000000205 | m2 | Stěna | 0.794 | 0.15 | 17.252 | 17.253 | 2.588 | 5.15 | 2.588 | 0.772 | 3.35 | Pset_WallCommon - AcousticRating: 41 dB
YTONG 150 | Půdorys 1.NP | YTONG 150 0.15 m | 1 | YTONG 150 | EI 180 | 1402HWa0798456945 | m3 | Celá stěna | Stávající | Zednické práce | YTONG 150 |  | 1402Stě0798456946 | m2 | Stěna | 0.794 | 0.15 | 1.34 | 1.34 | 0.201 | 0.4 | 0.201 | 0.06 | 3.35 | Pset_WallCommon - AcousticRating: 41 dB
YTONG 100 | Půdorys 1.NP | YTONG 100 0.1 m | 1 | YTONG 100 | EI 120 | 1402HWa0798457152 | m3 | Celá stěna | Stávající | Zednické práce | YTONG 100 | no | 1402Stě0798457153 | m2 | Stěna | 1.111 | 0.1 | 5.95 | 5.95 | 0.595 | 1.7 | 0.595 | 0.17 | 3.5 | Pset_WallCommon - AcousticRating: 37 dB
YTONG 150 | Půdorys 1.NP | YTONG 150 0.15 m | 1 | YTONG 150 | EI 180 | 1402HWa0798457047 | m3 | Celá stěna | Stávající | Zednické práce | YTONG 150 |  | 1402Stě0798457048 | m2 | Stěna | 0.794 | 0.15 | 18.76 | 18.76 | 2.814 | 5.6 | 2.814 | 0.84 | 3.35 | Pset_WallCommon - AcousticRating: 41 dB
YTONG 150 | Půdorys 1.NP | YTONG 150 0.15 m | 1 | YTONG 150 | EI 180 | 1402HWa0798457172 | m3 | Celá stěna | Stávající | Zednické práce | YTONG 150 |  | 1402Stě0798457174 | m2 | Stěna | 0.794 | 0.15 | 1.34 | 1.34 | 0.201 | 0.4 | 0.201 | 0.06 | 3.35 | Pset_WallCommon - AcousticRating: 41 dB
YTONG 150 | Půdorys 1.NP | YTONG 150 0.15 m | 1 | YTONG 150 | EI 180 | 1402HWa0798457195 | m3 | Celá stěna | Stávající | Zednické práce | YTONG 150 |  | 1402Stě0798457196 | m2 | Stěna | 0.794 | 0.15 | 5.695 | 5.695 | 0.854 | 1.7 | 0.854 | 0.255 | 3.35 | Pset_WallCommon - AcousticRating: 41 dB
YTONG 75 | Půdorys 1.NP | YTONG 75 0.075 m | 1 | YTONG 75 | EI 120 | 1402HWa0798457281 | m3 | Celá stěna | Stávající | Zednické práce | YTONG 75 | no | 1402Stě0798457282 | m2 | Stěna | 1.389 | 0.075 | 1.4 | 1.4 | 0.105 | 0.4 | 0.105 | 0.03 | 3.5 | Pset_WallCommon - AcousticRating: 34 dB
YTONG 75 | Půdorys 1.NP | YTONG 75 0.075 m | 1 | YTONG 75 | EI 120 | 1402HWa0798457291 | m3 | Celá stěna | Stávající | Zednické práce | YTONG 75 | no | 1402Stě0798457292 | m2 | Stěna | 1.389 | 0.075 | 0.665 | 0.665 | 0.05 | 0.19 | 0.05 | 0.014 | 3.5 | Pset_WallCommon - AcousticRating: 34 dB
YTONG 125 | Půdorys 1.NP | YTONG 125 0.125 m | 1 | YTONG 125 | EI 180 | 1402HWa0798457313 | m3 | Celá stěna | Stávající | Zednické práce | YTONG 125 | no | 1402Stě0798457314 | m2 | Stěna | 0.926 | 0.125 | 1.767 | 1.768 | 0.221 | 0.505 | 0.221 | 0.063 | 3.5 | Pset_WallCommon - AcousticRating: 39 dB
YTONG 125 | Půdorys 1.NP | YTONG 125 0.125 m | 1 | YTONG 125 | EI 180 | 1402HWa0798457323 | m3 | Celá stěna | Stávající | Zednické práce | YTONG 125 | no | 1402Stě0798457324 | m2 | Stěna | 0.926 | 0.125 | 1.767 | 1.768 | 0.221 | 0.505 | 0.221 | 0.063 | 3.5 | Pset_WallCommon - AcousticRating: 39 dB
YTONG 125 | Půdorys 1.NP | YTONG 125 0.125 m | 1 | YTONG 125 | EI 180 | 1402HWa0798457333 | m3 | Celá stěna | Stávající | Zednické práce | YTONG 125 | no | 1402Stě0798457334 | m2 | Stěna | 0.926 | 0.125 | 2.275 | 1.525 | 0.284 | 0.65 | 0.191 | 0.081 | 3.5 | Pset_WallCommon - AcousticRating: 39 dB
YTONG 100 | Půdorys 1.NP | YTONG 100 0.1 m | 1 | YTONG 100 | EI 120 | 1402HWa0798457157 | m3 | Celá stěna | Stávající | Zednické práce | YTONG 100 | no | 1402Stě0798457158 | m2 | Stěna | 1.111 | 0.1 | 6.125 | 4.509 | 0.613 | 1.75 | 0.451 | 0.175 | 3.5 | Pset_WallCommon - AcousticRating: 37 dB
YTONG 150 | Půdorys 1.NP | YTONG 150 0.15 m | 1 | YTONG 150 | EI 180 | 1402HWa0798457242 | m3 | Celá stěna | Stávající | Zednické práce | YTONG 150 |  | 1402Stě0798457243 | m2 | Stěna | 0.794 | 0.15 | 4.187 | 4.188 | 0.628 | 1.25 | 0.628 | 0.188 | 3.35 | Pset_WallCommon - AcousticRating: 41 dB
YTONG 125 | Půdorys 1.NP | YTONG 125 0.125 m | 1 | YTONG 125 | EI 180 | 1402HWa0798457272 | m3 | Celá stěna | Stávající | Zednické práce | YTONG 125 | no | 1402Stě0798457273 | m2 | Stěna | 0.926 | 0.125 | 6.125 | 4.105 | 0.766 | 1.75 | 0.513 | 0.219 | 3.5 | Pset_WallCommon - AcousticRating: 39 dB
YTONG 125 | Půdorys 1.NP | YTONG 125 0.125 m | 1 | YTONG 125 | EI 180 | 1402HWa0798457252 | m3 | Celá stěna | Stávající | Zednické práce | YTONG 125 | no | 1402Stě0798457253 | m2 | Stěna | 0.926 | 0.125 | 4.375 | 2.759 | 0.547 | 1.25 | 0.345 | 0.156 | 3.5 | Pset_WallCommon - AcousticRating: 39 dB
YTONG 150 | Půdorys 1.NP | YTONG 150 0.15 m |  | YTONG 150 | EI 180 | 1402HWa0798456901 | m3 | Celá stěna | Stávající | Zednické práce | YTONG 150 |  | 1402Stě0798456903 | m2 | Stěna | 0.794 | 0.15 | 5.025 | 2.601 | 0.754 | 1.5 | 0.39 | 0.225 | 3.35 | Pset_WallCommon - AcousticRating: 41 dB
YTONG 150 | Půdorys 1.NP | YTONG 150 0.15 m |  | YTONG 150 | EI 180 | 1402HWa0798456924 | m3 | Celá stěna | Stávající | Zednické práce | YTONG 150 |  | 1402Stě0798456926 | m2 | Stěna | 0.794 | 0.15 | 4.4 | 5.025 | 0.66 | 1.313 | 0.66 | 0.197 | 3.35 | Pset_WallCommon - AcousticRating: 41 dB
YTONG 150 | Půdorys 1.NP | YTONG 150 0.15 m | 1 | YTONG 150 | EI 180 | 1402HWa0798457985 | m3 | Celá stěna | Stávající | Zednické práce | YTONG 150 |  | 1402Stě0798457986 | m2 | Stěna | 0.794 | 0.15 | 12.981 | 9.571 | 1.947 | 3.875 | 1.436 | 0.581 | 3.35 | Pset_WallCommon - AcousticRating: 41 dB
PÓROBETONOVÉ ZDIVO | Půdorys 1.NP | PÓROBETONOVÉ ZDIVO 0.1 m | 1 | PÓROBETONOVÉ ZDIVO | EI 120 | 1402HWa0798457035 | m3 | Celá stěna | Stávající | Zednické práce | PÓROBETONOVÉ ZDIVO |  | 1402Stě0798457036 | m2 | Stěna | 1.111 | 0.1 | 17.588 | 14.178 | 1.759 | 5.25 | 1.418 | 0.525 | 3.35 | Pset_WallCommon - AcousticRating: 37 dB
YTONG 150 | Půdorys 1.NP | YTONG 150 0.15 m |  | YTONG 150 | EI 180 | 1402HWa0798458392 | m3 | Celá stěna | Stávající | Zednické práce | YTONG 150 |  | 1402Stě0798458393 | m2 | Stěna | 0.794 | 0.15 | 4.6 | 4.6 | 0.69 | 4 | 0.69 | 0.6 | 1.15 | Pset_WallCommon - AcousticRating: 41 dB
YTONG 150 | Půdorys 1.NP | YTONG 150 0.15 m | 1 | YTONG 150 | EI 180 | 1402HWa0798458423 | m3 | Celá stěna | Stávající | Zednické práce | YTONG 150 |  | 1402Stě0798458424 | m2 | Stěna | 0.794 | 0.15 | 5.193 | 5.193 | 0.779 | 1.55 | 0.779 | 0.232 | 3.35 | Pset_WallCommon - AcousticRating: 41 dB
YTONG 150 | Půdorys 1.NP | YTONG 150 0.15 m | 1 | YTONG 150 | EI 180 | 1402HWa0798458430 | m3 | Celá stěna | Stávající | Zednické práce | YTONG 150 |  | 1402Stě0798458431 | m2 | Stěna | 0.794 | 0.15 | 1.34 | 1.34 | 0.201 | 0.4 | 0.201 | 0.06 | 3.35 | Pset_WallCommon - AcousticRating: 41 dB
YTONG 150 | Půdorys 1.NP | YTONG 150 0.15 m | 1 | YTONG 150 | EI 180 | 1402HWa0798458442 | m3 | Celá stěna | Stávající | Zednické práce | YTONG 150 |  | 1402Stě0798458443 | m2 | Stěna | 0.794 | 0.15 | 3.015 | 3.015 | 0.452 | 0.9 | 0.452 | 0.135 | 3.35 | Pset_WallCommon - AcousticRating: 41 dB
PROSKLENÁ PŘÍČKA JEDNODUCHÁ | Půdorys 1.NP | PROSKLENÁ PŘÍČKA JEDNODUCHÁ 0.05 m | 1 | PROSKLENÁ PŘÍČKA JEDNODUCHÁ |  | 1402HWa0798458455 | m3 | Celá stěna | Stávající | Sklenářské práce | PROSKLENÁ PŘÍČKA JEDNODUCHÁ | no | 1402Stě0798458456 | m2 | Stěna | 0 | 0.05 | 9.912 | 6.868 | 0.496 | 3.05 | 0.343 | 0.153 | 3.25 | Pset_WallCommon - AcousticRating: 32 - 39 dB
PROSKLENÁ PŘÍČKA JEDNODUCHÁ | Půdorys 1.NP | PROSKLENÁ PŘÍČKA JEDNODUCHÁ 0.05 m | 1 | PROSKLENÁ PŘÍČKA JEDNODUCHÁ |  | 1402HWa0798458465 | m3 | Celá stěna | Stávající | Sklenářské práce | PROSKLENÁ PŘÍČKA JEDNODUCHÁ | no | 1402Stě0798458466 | m2 | Stěna | 0 | 0.05 | 10.4 | 7.355 | 0.52 | 3.2 | 0.368 | 0.16 | 3.25 | Pset_WallCommon - AcousticRating: 32 - 39 dB
PROSKLENÁ PŘÍČKA JEDNODUCHÁ | Půdorys 1.NP | PROSKLENÁ PŘÍČKA JEDNODUCHÁ 0.05 m | 1 | PROSKLENÁ PŘÍČKA JEDNODUCHÁ |  | 1402HWa0798458470 | m3 | Celá stěna | Stávající | Sklenářské práce | PROSKLENÁ PŘÍČKA JEDNODUCHÁ | no | 1402Stě0798458471 | m2 | Stěna | 0 | 0.05 | 10.887 | 10.888 | 0.544 | 3.35 | 0.544 | 0.167 | 3.25 | Pset_WallCommon - AcousticRating: 32 - 39 dB
PROSKLENÁ PŘÍČKA JEDNODUCHÁ | Půdorys 1.NP | PROSKLENÁ PŘÍČKA JEDNODUCHÁ 0.05 m | 1 | PROSKLENÁ PŘÍČKA JEDNODUCHÁ |  | 1402HWa0798458476 | m3 | Celá stěna | Stávající | Sklenářské práce | PROSKLENÁ PŘÍČKA JEDNODUCHÁ | no | 1402Stě0798458477 | m2 | Stěna | 0 | 0.05 | 5.85 | 5.85 | 0.293 | 1.8 | 0.293 | 0.09 | 3.25 | Pset_WallCommon - AcousticRating: 32 - 39 dB
PROSKLENÁ PŘÍČKA JEDNODUCHÁ | Půdorys 1.NP | PROSKLENÁ PŘÍČKA JEDNODUCHÁ 0.05 m | 1 | PROSKLENÁ PŘÍČKA JEDNODUCHÁ |  | 1402HWa0798458481 | m3 | Celá stěna | Stávající | Sklenářské práce | PROSKLENÁ PŘÍČKA JEDNODUCHÁ | no | 1402Stě0798458482 | m2 | Stěna | 0 | 0.05 | 5.85 | 5.85 | 0.293 | 1.8 | 0.293 | 0.09 | 3.25 | Pset_WallCommon - AcousticRating: 32 - 39 dB
PROSKLENÁ PŘÍČKA JEDNODUCHÁ | Půdorys 1.NP | PROSKLENÁ PŘÍČKA JEDNODUCHÁ 0.05 m | 1 | PROSKLENÁ PŘÍČKA JEDNODUCHÁ |  | 1402HWa0798458484 | m3 | Celá stěna | Stávající | Sklenářské práce | PROSKLENÁ PŘÍČKA JEDNODUCHÁ | no | 1402Stě0798458485 | m2 | Stěna | 0 | 0.05 | 5.85 | 5.85 | 0.293 | 1.8 | 0.293 | 0.09 | 3.25 | Pset_WallCommon - AcousticRating: 32 - 39 dB
PÓROBETONOVÉ ZDIVO | Půdorys 1.NP | PÓROBETONOVÉ ZDIVO 0.1 m | 1 | PÓROBETONOVÉ ZDIVO | EI 120 | 1402HWa0798458730 | m3 | Celá stěna | Stávající | Zednické práce | PÓROBETONOVÉ ZDIVO |  | 1402Stě0798458731 | m2 | Stěna | 1.111 | 0.1 | 18.09 | 18.09 | 1.809 | 5.4 | 1.809 | 0.54 | 3.35 | Pset_WallCommon - AcousticRating: 37 dB
PÓROBETONOVÉ ZDIVO | Půdorys 1.NP | PÓROBETONOVÉ ZDIVO 0.1 m | 1 | PÓROBETONOVÉ ZDIVO | EI 120 | 1402HWa0798458743 | m3 | Celá stěna | Stávající | Zednické práce | PÓROBETONOVÉ ZDIVO |  | 1402Stě0798458744 | m2 | Stěna | 1.111 | 0.1 | 18.09 | 18.09 | 1.809 | 5.4 | 1.809 | 0.54 | 3.35 | Pset_WallCommon - AcousticRating: 37 dB
YTONG 150 | Půdorys 1.NP | YTONG 150 0.15 m | 1 | YTONG 150 | EI 180 | 1402HWa0798458755 | m3 | Celá stěna | Stávající | Zednické práce | YTONG 150 |  | 1402Stě0798458756 | m2 | Stěna | 0.794 | 0.15 | 22.78 | 18.336 | 3.417 | 6.8 | 2.75 | 1.02 | 3.35 | Pset_WallCommon - AcousticRating: 41 dB
ZDIVO Z CDm | Půdorys 1.NP | ZDIVO Z CDm 0.125 m | 1 | ZDIVO Z CDm | A | 1402HWa0798458891 | m3 | Celá stěna | Stávající | Zednické práce | ZDIVO Z CDm | yes | 1402Stě0798458892 | m3 | Stěna | 0 | 0.125 | 2.596 | 2.596 | 0.325 | 0.775 | 0.325 | 0.097 | 3.35
YTONG 150 | Půdorys 1.NP | YTONG 150 0.15 m | 1 | YTONG 150 | EI 180 | 1402HWa0798458936 | m3 | Celá stěna | Stávající | Zednické práce | YTONG 150 |  | 1402Stě0798458937 | m2 | Stěna | 0.794 | 0.15 | 10.72 | 7.488 | 1.608 | 3.2 | 1.123 | 0.48 | 3.35 | Pset_WallCommon - AcousticRating: 41 dB
ZDIVO Z CDm | Půdorys 1.NP | ZDIVO Z CDm 0.125 m | 1 | ZDIVO Z CDm | A | 1402HWa0798458949 | m3 | Celá stěna | Stávající | Zednické práce | ZDIVO Z CDm | yes | 1402Stě0798458950 | m3 | Stěna | 0 | 0.125 | 2.63 | 2.63 | 0.329 | 0.785 | 0.329 | 0.098 | 3.35
ZDIVO Z CDm | Půdorys 1.NP | ZDIVO Z CDm 0.125 m | 1 | ZDIVO Z CDm | A | 1402HWa0798458978 | m3 | Celá stěna | Stávající | Zednické práce | ZDIVO Z CDm | yes | 1402Stě0798458979 | m3 | Stěna | 0 | 0.125 | 3.434 | 3.434 | 0.429 | 1.025 | 0.429 | 0.128 | 3.35
ZDIVO Z CDm | Půdorys 1.NP | ZDIVO Z CDm 0.125 m | 1 | ZDIVO Z CDm | A | 1402HWa0798458998 | m3 | Celá stěna | Stávající | Zednické práce | ZDIVO Z CDm | yes | 1402Stě0798458999 | m3 | Stěna | 0 | 0.125 | 0.871 | 0.871 | 0.109 | 0.26 | 0.109 | 0.032 | 3.35
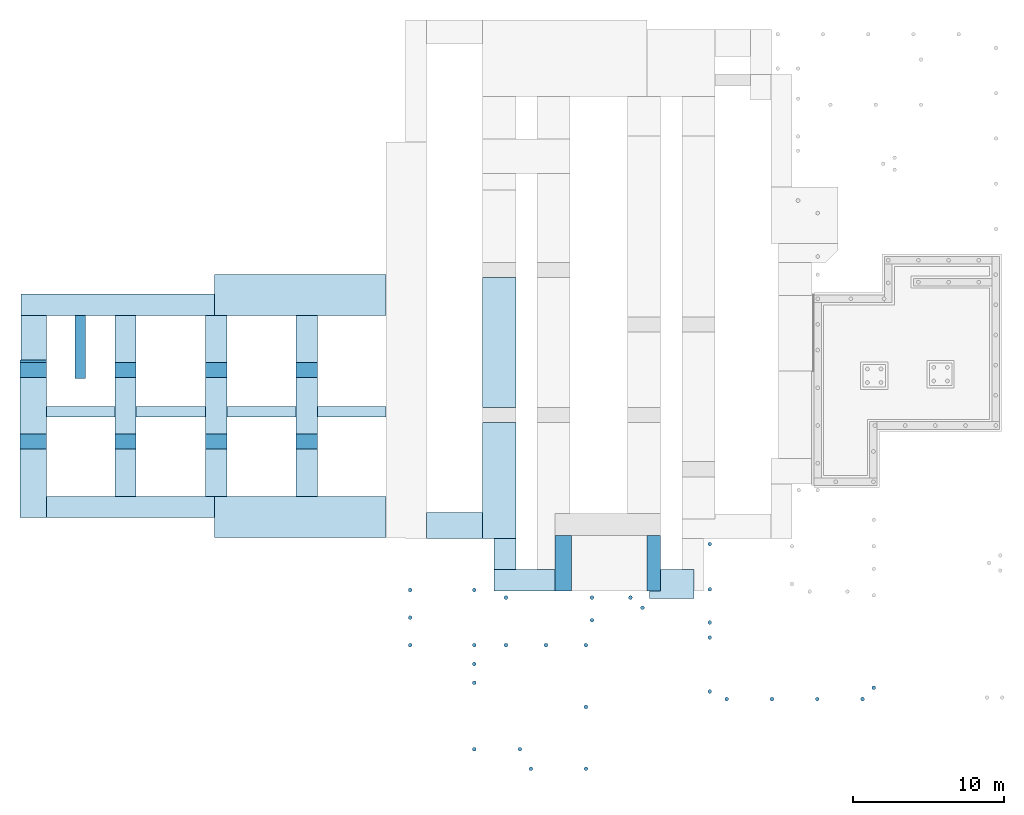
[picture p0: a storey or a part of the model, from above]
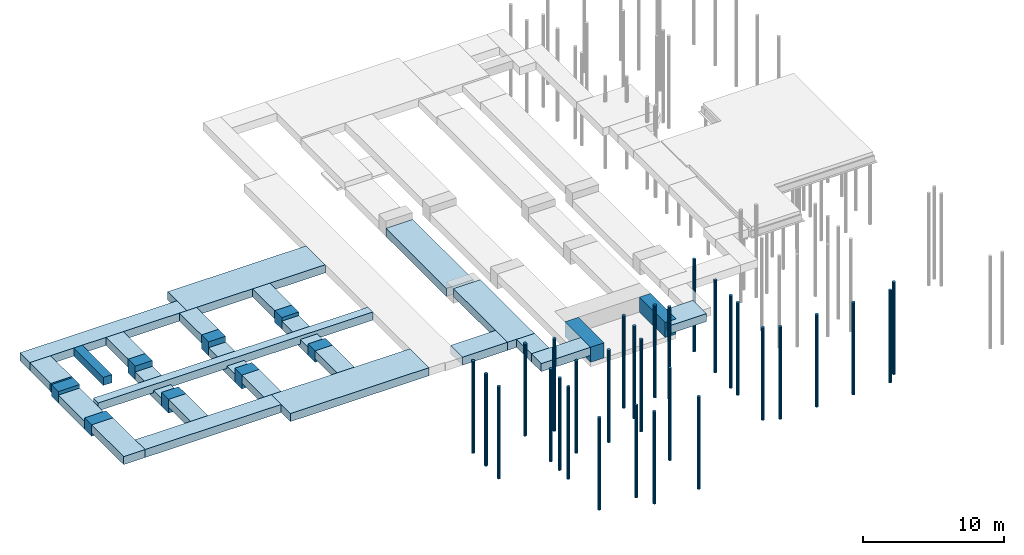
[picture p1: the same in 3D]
Properties of the parts of a building model (IFC4), part 24 of 45

# IfcWall (2385)
Name | In | Material | Faktor | Označení | Požární odolnost | Allright_Stavebni_dil_ID | Jednotka | Název_objektu | Object Layer Attributes #1, Status | Object Layer Attributes #1, Práce | Object Layer Attributes #1, Materiál | Object Layer Attributes #1, Staticky nosná konstrukce | Object Layer Attributes #1, Allright_Stavebni_dil_ID | Object Layer Attributes #1, Jednotka | Object Layer Attributes #1, Název_objektu | ThermalTransmittance (W/K/m2) | Width (m) | GrossSideArea (m2) | NetSideArea (m2) | GrossVolume (m3) | Length (m) | NetVolume (m3) | GrossFootprintArea (m2) | Height (m)
YTONG 125 | Půdorys 1.NP | YTONG 125 0.125 m | 1 | YTONG 125 | EI 180 | 1402HWa0798458960 | m3 | Celá stěna | Stávající | Zednické práce | YTONG 125 | no | 1402Stě0798458961 | m2 | Stěna | 0.926 | 0.125 | 3.5 | 3.5 | 0.437 | 1 | 0.437 | 0.125 | 3.5 | Pset_WallCommon - AcousticRating: 39 dB
YTONG 125 | Půdorys 1.NP | YTONG 125 0.125 m | 1 | YTONG 125 | EI 180 | 1402HWa0798459162 | m3 | Celá stěna | Stávající | Zednické práce | YTONG 125 | no | 1402Stě0798459163 | m2 | Stěna | 0.926 | 0.125 | 1.33 | 1.33 | 0.166 | 0.38 | 0.166 | 0.047 | 3.5 | Pset_WallCommon - AcousticRating: 39 dB
YTONG 125 | Půdorys 1.NP | YTONG 125 0.125 m | 1 | YTONG 125 | EI 180 | 1402HWa0798459172 | m3 | Celá stěna | Stávající | Zednické práce | YTONG 125 | no | 1402Stě0798459173 | m2 | Stěna | 0.926 | 0.125 | 1.942 | 1.943 | 0.243 | 0.555 | 0.243 | 0.069 | 3.5 | Pset_WallCommon - AcousticRating: 39 dB
YTONG 125 | Půdorys 1.NP | YTONG 125 0.125 m | 1 | YTONG 125 | EI 180 | 1402HWa0798459183 | m3 | Celá stěna | Stávající | Zednické práce | YTONG 125 | no | 1402Stě0798459184 | m2 | Stěna | 0.926 | 0.125 | 0.892 | 0.893 | 0.112 | 0.255 | 0.112 | 0.032 | 3.5 | Pset_WallCommon - AcousticRating: 39 dB
ZDIVO Z CDm | Půdorys 1.NP | ZDIVO Z CDm 0.125 m | 1 | ZDIVO Z CDm | A | 1402HWa0000000355 | m3 | Celá stěna | Stávající | Zednické práce | ZDIVO Z CDm | yes | 1402Stě0000000356 | m3 | Stěna | 0 | 0.125 | 10.469 | 8.045 | 1.309 | 3.125 | 1.006 | 0.391 | 3.35
ZDIVO Z CDm | Půdorys 1.NP | ZDIVO Z CDm 0.125 m | 1 | ZDIVO Z CDm | A | 1402HWa0000000348 | m3 | Celá stěna | Stávající | Zednické práce | ZDIVO Z CDm | yes | 1402Stě0000000349 | m3 | Stěna | 0 | 0.125 | 10.05 | 10.05 | 1.256 | 3 | 1.256 | 0.375 | 3.35
ZDIVO Z CDm | Půdorys 1.NP | ZDIVO Z CDm 0.125 m | 1 | ZDIVO Z CDm | A | 1402HWa0798456708 | m3 | Celá stěna | Stávající | Zednické práce | ZDIVO Z CDm | yes | 1402Stě0798456709 | m3 | Stěna | 0 | 0.125 | 26.297 | 23.874 | 3.287 | 7.85 | 2.984 | 0.981 | 3.35
ZDIVO Z CDm | Půdorys 1.NP | ZDIVO Z CDm 0.125 m | 1 | ZDIVO Z CDm | A | 1402HWa0798454048 | m3 | Celá stěna | Stávající | Zednické práce | ZDIVO Z CDm | yes | 1402Stě0798454049 | m3 | Stěna | 0 | 0.125 | 23.45 | 17.2 | 2.931 | 7 | 2.15 | 0.875 | 3.35
STÁVAJÍCÍ KCE | Půdorys 1.NP | MINERÁLNÍ VATA 0.1 m, STÁVAJÍC KCE 0.4 m | 1 | STÁVAJÍCÍ KCE | REI 180 | 1402HWa0798460048 | m3 | Celá stěna | Stávající | Zateplovací systémy | MINERÁLNÍ VATA | no | 1402Stě0798460049 | m2 | Stěna | 0.541 | 0.5 | 44.736 | 39.876 | 21.296 | 9.52 | 18.866 | 4.7 | 4.8 | NEMSOK - Object Layer Attributes #2, 2D interakce: yes; Object Layer Attributes #2, Status: Stávající; Object Layer Attributes #2, Práce: Zednické práce; Object Layer Attributes #2, Materiál: STÁVAJÍC KCE; Object Layer Attributes #2, Allright_Stavebni_dil_ID: 1402Stě0798460050; Object Layer Attributes #2, Jednotka: m3; Object Layer Attributes #2, Název_objektu: Stěna; Object Layer Attributes #2, Staticky nosná konstrukce: yes; Pset_WallCommon - AcousticRating: 48 dB
STÁVAJÍCÍ KCE | Půdorys 1.NP | MINERÁLNÍ VATA 0.1 m, STÁVAJÍC KCE 0.4 m | 1 | STÁVAJÍCÍ KCE | REI 180 | 1402HWa0798460030 | m3 | Celá stěna | Stávající | Zateplovací systémy | MINERÁLNÍ VATA | no | 1402Stě0798460031 | m2 | Stěna | 0.541 | 0.5 | 40.08 | 40.08 | 19.235 | 8.75 | 19.235 | 4.255 | 4.8 | NEMSOK - Object Layer Attributes #2, 2D interakce: yes; Object Layer Attributes #2, Status: Stávající; Object Layer Attributes #2, Práce: Zednické práce; Object Layer Attributes #2, Materiál: STÁVAJÍC KCE; Object Layer Attributes #2, Allright_Stavebni_dil_ID: 1402Stě0798460032; Object Layer Attributes #2, Jednotka: m3; Object Layer Attributes #2, Název_objektu: Stěna; Object Layer Attributes #2, Staticky nosná konstrukce: yes; Pset_WallCommon - AcousticRating: 48 dB
STÁVAJÍCÍ KCE | Půdorys 1.NP | MINERÁLNÍ VATA 0.1 m, STÁVAJÍC KCE 0.4 m | 1 | STÁVAJÍCÍ KCE | REI 180 | 1402HWa0798460022 | m3 | Celá stěna | Stávající | Zateplovací systémy | MINERÁLNÍ VATA | no | 1402Stě0798460023 | m2 | Stěna | 0.541 | 0.5 | 46.176 | 44.556 | 21.872 | 9.67 | 21.062 | 4.82 | 4.8 | NEMSOK - Object Layer Attributes #2, 2D interakce: yes; Object Layer Attributes #2, Status: Stávající; Object Layer Attributes #2, Práce: Zednické práce; Object Layer Attributes #2, Materiál: STÁVAJÍC KCE; Object Layer Attributes #2, Allright_Stavebni_dil_ID: 1402Stě0798460024; Object Layer Attributes #2, Jednotka: m3; Object Layer Attributes #2, Název_objektu: Stěna; Object Layer Attributes #2, Staticky nosná konstrukce: yes; Pset_WallCommon - AcousticRating: 48 dB
PÓROBETONOVÉ ZDIVO | Půdorys 1.NP | PÓROBETONOVÉ ZDIVO 0.1 m |  | PÓROBETONOVÉ ZDIVO | EI 120 | 1402HWa0798452599 | m3 | Celá stěna | Stávající | Zednické práce | PÓROBETONOVÉ ZDIVO |  | 1402Stě0798452603 | m2 | Stěna | 1.111 | 0.1 | 10.72 | 9.55 | 1.072 | 3.2 | 0.955 | 0.32 | 3.35 | Pset_WallCommon - AcousticRating: 37 dB
ZELEZOBETONOVÁ KCE | Půdorys 1.NP | ZELEZOBETONOVÁ KCE 0.25 m, MINERÁLNÍ VATA 0.12 m |  | ZELEZOBETONOVÁ KCE | A | 1402HWa0000000392 | m3 | Celá stěna | Stávající | Betonářské práce | ZELEZOBETONOVÁ KCE | no | 1402Stě0000000393 | m3 | Stěna | 0 | 0.37 | 5.472 | 4.392 | 1.956 | 1.46 | 1.556 | 0.548 | 3.6 | NEMSOK - Object Layer Attributes #2, 2D interakce: yes; Object Layer Attributes #2, Status: Stávající; Object Layer Attributes #2, Práce: Zateplovací systémy; Object Layer Attributes #2, Materiál: MINERÁLNÍ VATA; Object Layer Attributes #2, Allright_Stavebni_dil_ID: 1402Stě0000000526; Object Layer Attributes #2, Jednotka: m2; Object Layer Attributes #2, Název_objektu: Stěna; Object Layer Attributes #2, Staticky nosná konstrukce: no
ZELEZOBETONOVÁ KCE | Půdorys 1.NP | ZELEZOBETONOVÁ KCE 0.25 m, PERIMETR 0.05 m | 1 | ZELEZOBETONOVÁ KCE | A | 1402HWa0798460482 | m3 | Celá stěna | Stávající | Betonářské práce | ZELEZOBETONOVÁ KCE | no | 1402Stě0798460568 | m3 | Stěna | 0 | 0.3 | 33.66 | 30.8 | 9.934 | 9.35 | 9.076 | 2.805 | 3.6 | NEMSOK - Object Layer Attributes #2, 2D interakce: yes; Object Layer Attributes #2, Status: Stávající; Object Layer Attributes #2, Práce: Zateplovací systémy; Object Layer Attributes #2, Materiál: PERIMETR; Object Layer Attributes #2, Allright_Stavebni_dil_ID: 1402Stě0798460566; Object Layer Attributes #2, Jednotka: m2; Object Layer Attributes #2, Název_objektu: Stěna; Object Layer Attributes #2, Staticky nosná konstrukce: no
STÁVAJÍCÍ KCE | Půdorys 1.NP | STÁVAJÍC KCE 0.3 m | 1 | STÁVAJÍCÍ KCE | REI 180 | 1402HWa0798462238 | m3 | Celá stěna | Stávající | Zednické práce | STÁVAJÍC KCE |  | 1402Stě0798462239 | m3 | Stěna | 0.541 | 0.3 | 42 | 38.48 | 12.6 | 8.75 | 11.544 | 2.625 | 4.8 | Pset_WallCommon - AcousticRating: 48 dB
ZELEZOBETONOVÁ KCE | Půdorys 1.NP | ZELEZOBETONOVÁ KCE 0.3 m, MINERÁLNÍ VATA 0.12 m | 1 | ZELEZOBETONOVÁ KCE | A | 1402HWa0798438678 | m3 | Celá stěna | Stávající | Betonářské práce | ZELEZOBETONOVÁ KCE | no | 1402Stě0798438680 | m3 | Stěna | 0 | 0.42 | 24.85 | 24.85 | 10.326 | 6.95 | 10.326 | 2.892 | 3.6 | NEMSOK - Object Layer Attributes #2, 2D interakce: yes; Object Layer Attributes #2, Status: Stávající; Object Layer Attributes #2, Práce: Zateplovací systémy; Object Layer Attributes #2, Materiál: MINERÁLNÍ VATA; Object Layer Attributes #2, Allright_Stavebni_dil_ID: 1402Stě0798438679; Object Layer Attributes #2, Jednotka: m2; Object Layer Attributes #2, Název_objektu: Stěna; Object Layer Attributes #2, Staticky nosná konstrukce: no
ZDIVO Z CDm | Půdorys 1.NP | ZDIVO Z CDm 0.125 m | 1 | ZDIVO Z CDm | A | 1402HWa0798463180 | m3 | Celá stěna | Stávající | Zednické práce | ZDIVO Z CDm | yes | 1402Stě0798463181 | m3 | Stěna | 0 | 0.125 | 28.81 | 25.174 | 3.601 | 8.6 | 3.147 | 1.075 | 3.35
ZDIVO Z CDm | Půdorys 1.NP | ZDIVO Z CDm 0.125 m | 1 | ZDIVO Z CDm | A | 1402HWa0798463191 | m3 | Celá stěna | Stávající | Zednické práce | ZDIVO Z CDm | yes | 1402Stě0798463192 | m3 | Stěna | 0 | 0.125 | 2.01 | 2.01 | 0.251 | 0.6 | 0.251 | 0.075 | 3.35
ZDIVO Z CDm | Půdorys 1.NP | ZDIVO Z CDm 0.125 m | 1 | ZDIVO Z CDm | A | 1402HWa0798463197 | m3 | Celá stěna | Stávající | Zednické práce | ZDIVO Z CDm | yes | 1402Stě0798463198 | m3 | Stěna | 0 | 0.125 | 1.675 | 1.675 | 0.209 | 0.5 | 0.209 | 0.063 | 3.35
ZELEZOBETONOVÁ KCE | Půdorys 1.NP | ZELEZOBETONOVÁ KCE 0.3 m, MINERÁLNÍ VATA 0.12 m | 1 | ZELEZOBETONOVÁ KCE | A | 1402HWa0000000683 | m3 | Celá stěna | Stávající | Betonářské práce | ZELEZOBETONOVÁ KCE | no | 1402Stě0000000684 | m3 | Stěna | 0 | 0.42 | 24.85 | 24.85 | 10.326 | 6.95 | 10.326 | 2.892 | 3.6 | NEMSOK - Object Layer Attributes #2, 2D interakce: yes; Object Layer Attributes #2, Status: Stávající; Object Layer Attributes #2, Práce: Zateplovací systémy; Object Layer Attributes #2, Materiál: MINERÁLNÍ VATA; Object Layer Attributes #2, Allright_Stavebni_dil_ID: 1402Stě0000000685; Object Layer Attributes #2, Jednotka: m2; Object Layer Attributes #2, Název_objektu: Stěna; Object Layer Attributes #2, Staticky nosná konstrukce: no
PÓROBETONOVÉ ZDIVO | Půdorys 1.NP | PÓROBETONOVÉ ZDIVO 0.1 m | 1 | PÓROBETONOVÉ ZDIVO | EI 120 | 1402HWa0798439187 | m3 | Celá stěna | Stávající | Zednické práce | PÓROBETONOVÉ ZDIVO |  | 1402Stě0798439188 | m2 | Stěna | 1.111 | 0.1 | 21.44 | 21.44 | 2.144 | 6.4 | 2.144 | 0.64 | 3.35 | Pset_WallCommon - AcousticRating: 37 dB
ZDIVO Z CDm | Půdorys 1.NP | ZDIVO Z CDm 0.125 m | 1 | ZDIVO Z CDm | A | 1402HWa0798463231 | m3 | Celá stěna | Stávající | Zednické práce | ZDIVO Z CDm | yes | 1402Stě0798463232 | m3 | Stěna | 0 | 0.125 | 3.35 | 3.35 | 0.419 | 1 | 0.419 | 0.125 | 3.35
ZDIVO Z CDm | Půdorys 1.NP | ZDIVO Z CDm 0.125 m | 1 | ZDIVO Z CDm | A | 1402HWa0798463248 | m3 | Celá stěna | Stávající | Zednické práce | ZDIVO Z CDm | yes | 1402Stě0798463249 | m3 | Stěna | 0 | 0.125 | 2.01 | 2.01 | 0.251 | 0.6 | 0.251 | 0.075 | 3.35
ZDIVO Z CDm | Půdorys 1.NP | ZDIVO Z CDm 0.125 m | 1 | ZDIVO Z CDm | A | 1402HWa0798463255 | m3 | Celá stěna | Stávající | Zednické práce | ZDIVO Z CDm | yes | 1402Stě0798463256 | m3 | Stěna | 0 | 0.125 | 10.72 | 10.72 | 1.34 | 3.2 | 1.34 | 0.4 | 3.35
ZDIVO Z CDm | Půdorys 1.NP | ZDIVO Z CDm 0.125 m | 1 | ZDIVO Z CDm | A | 1402HWa0798463264 | m3 | Celá stěna | Stávající | Zednické práce | ZDIVO Z CDm | yes | 1402Stě0798463265 | m3 | Stěna | 0 | 0.125 | 2.01 | 2.01 | 0.251 | 0.6 | 0.251 | 0.075 | 3.35
ZDIVO Z CDm | Půdorys 1.NP | ZDIVO Z CDm 0.125 m | 1 | ZDIVO Z CDm | A | 1402HWa0798463274 | m3 | Celá stěna | Stávající | Zednické práce | ZDIVO Z CDm | yes | 1402Stě0798463275 | m3 | Stěna | 0 | 0.125 | 2.01 | 2.01 | 0.251 | 0.6 | 0.251 | 0.075 | 3.35
ZDIVO Z CDm | Půdorys 1.NP | ZDIVO Z CDm 0.125 m | 1 | ZDIVO Z CDm | A | 1402HWa0798463352 | m3 | Celá stěna | Stávající | Zednické práce | ZDIVO Z CDm |  | 1402Stě0798463354 | m3 | Stěna | 0 | 0.125 | 18.09 | 18.09 | 2.261 | 5.4 | 2.261 | 0.675 | 3.35
ZDIVO Z CDm | Půdorys 1.NP | ZDIVO Z CDm 0.125 m | 1 | ZDIVO Z CDm | A | 1402HWa0798463359 | m3 | Celá stěna | Stávající | Zednické práce | ZDIVO Z CDm |  | 1402Stě0798463361 | m3 | Stěna | 0 | 0.125 | 17.671 | 17.671 | 2.209 | 5.275 | 2.209 | 0.659 | 3.35
YTONG 150 | Půdorys 1.NP | YTONG 150 0.15 m | 1 | YTONG 150 | EI 180 | 1402HWa0798463405 | m3 | Celá stěna | Stávající | Zednické práce | YTONG 150 |  | 1402Stě0798463406 | m2 | Stěna | 0.794 | 0.15 | 13.166 | 13.166 | 1.975 | 3.93 | 1.975 | 0.59 | 3.35 | Pset_WallCommon - AcousticRating: 41 dB
YTONG 150 | Půdorys 1.NP | YTONG 150 0.15 m | 1 | YTONG 150 | EI 180 | 1402HWa0798463412 | m3 | Celá stěna | Stávající | Zednické práce | YTONG 150 |  | 1402Stě0798463413 | m2 | Stěna | 0.794 | 0.15 | 13.668 | 13.668 | 2.05 | 4.08 | 2.05 | 0.612 | 3.35 | Pset_WallCommon - AcousticRating: 41 dB
YTONG 125 | Půdorys 1.NP | YTONG 125 0.125 m | 1 | YTONG 125 | EI 180 | 1402HWa0798463434 | m3 | Celá stěna | Stávající | Zednické práce | YTONG 125 | no | 1402Stě0798463435 | m2 | Stěna | 0.926 | 0.125 | 14.945 | 12.925 | 1.868 | 4.27 | 1.616 | 0.534 | 3.5 | Pset_WallCommon - AcousticRating: 39 dB
PÓROBETONOVÉ ZDIVO | Půdorys 1.NP | PÓROBETONOVÉ ZDIVO 0.1 m | 1 | PÓROBETONOVÉ ZDIVO | EI 120 | 1402HWa0798463452 | m3 | Celá stěna | Stávající | Zednické práce | PÓROBETONOVÉ ZDIVO |  | 1402Stě0798463453 | m2 | Stěna | 1.111 | 0.1 | 21.44 | 21.44 | 2.144 | 6.4 | 2.144 | 0.64 | 3.35 | Pset_WallCommon - AcousticRating: 37 dB
ZDIVO Z CDm | Půdorys 1.NP | ZDIVO Z CDm 0.125 m | 1 | ZDIVO Z CDm | A | 1402HWa0798463708 | m3 | Celá stěna | Stávající | Zednické práce | ZDIVO Z CDm |  | 1402Stě0798463709 | m3 | Stěna | 0 | 0.125 | 5.695 | 5.695 | 0.712 | 1.7 | 0.712 | 0.212 | 3.35
ZDIVO Z CDm | Půdorys 1.NP | ZDIVO Z CDm 0.125 m | 1 | ZDIVO Z CDm | A | 1402HWa0798463720 | m3 | Celá stěna | Stávající | Zednické práce | ZDIVO Z CDm | yes | 1402Stě0798463738 | m3 | Stěna | 0 | 0.125 | 9.715 | 9.715 | 1.214 | 2.9 | 1.214 | 0.363 | 3.35
ZDIVO Z CDm | Půdorys 1.NP | ZDIVO Z CDm 0.125 m | 1 | ZDIVO Z CDm | A | 1402HWa0798463721 | m3 | Celá stěna | Stávající | Zednické práce | ZDIVO Z CDm | yes | 1402Stě0798463745 | m3 | Stěna | 0 | 0.125 | 11.474 | 11.474 | 1.434 | 3.425 | 1.434 | 0.428 | 3.35
ZDIVO Z CDm | Půdorys 1.NP | ZDIVO Z CDm 0.125 m | 1 | ZDIVO Z CDm | A | 1402HWa0798463724 | m3 | Celá stěna | Stávající | Zednické práce | ZDIVO Z CDm | yes | 1402Stě0798463737 | m3 | Stěna | 0 | 0.125 | 10.804 | 8.986 | 1.35 | 3.225 | 1.123 | 0.403 | 3.35
ZDIVO Z CDm | Půdorys 1.NP | ZDIVO Z CDm 0.125 m | 1 | ZDIVO Z CDm | A | 1402HWa0798463671 | m3 | Celá stěna | Stávající | Zednické práce | ZDIVO Z CDm | yes | 1402Stě0798463707 | m3 | Stěna | 0 | 0.125 | 25.041 | 20.395 | 3.13 | 7.475 | 2.549 | 0.934 | 3.35
ZDIVO Z CDm | Půdorys 1.NP | ZDIVO Z CDm 0.125 m | 1 | ZDIVO Z CDm | A | 1402HWa0798463756 | m3 | Celá stěna | Stávající | Zednické práce | ZDIVO Z CDm | yes | 1402Stě0798463813 | m3 | Stěna | 0 | 0.125 | 25.041 | 17.567 | 3.13 | 7.475 | 2.196 | 0.934 | 3.35
ZDIVO Z CDm | Půdorys 1.NP | ZDIVO Z CDm 0.125 m | 1 | ZDIVO Z CDm | A | 1402HWa0798463956 | m3 | Celá stěna | Stávající | Zednické práce | ZDIVO Z CDm | yes | 1402Stě0798463957 | m3 | Stěna | 0 | 0.125 | 5.695 | 5.695 | 0.712 | 1.7 | 0.712 | 0.212 | 3.35
ZDIVO Z CDm | Půdorys 1.NP | ZDIVO Z CDm 0.125 m | 1 | ZDIVO Z CDm | A | 1402HWa0798463968 | m3 | Celá stěna | Stávající | Zednické práce | ZDIVO Z CDm | yes | 1402Stě0798463969 | m3 | Stěna | 0 | 0.125 | 6.867 | 7.035 | 0.858 | 2.05 | 0.858 | 0.256 | 3.35
ZDIVO Z CDm | Půdorys 1.NP | ZDIVO Z CDm 0.125 m | 1 | ZDIVO Z CDm | A | 1402HWa0798463983 | m3 | Celá stěna | Stávající | Zednické práce | ZDIVO Z CDm | yes | 1402Stě0798463984 | m3 | Stěna | 0 | 0.125 | 7.035 | 7.035 | 0.879 | 2.1 | 0.879 | 0.262 | 3.35
ZDIVO Z CDm | Půdorys 1.NP | ZDIVO Z CDm 0.125 m | 1 | ZDIVO Z CDm | A | 1402HWa0798464012 | m3 | Celá stěna | Stávající | Zednické práce | ZDIVO Z CDm | yes | 1402Stě0798464025 | m3 | Stěna | 0 | 0.125 | 5.025 | 3.611 | 0.628 | 1.5 | 0.451 | 0.188 | 3.35
ZDIVO Z CDm | Půdorys 1.NP | ZDIVO Z CDm 0.125 m | 1 | ZDIVO Z CDm | A | 1402HWa0798453714 | m3 | Celá stěna | Stávající | Zednické práce | ZDIVO Z CDm | yes | 1402Stě0798453715 | m3 | Stěna | 0 | 0.125 | 10.72 | 8.902 | 1.34 | 3.2 | 1.113 | 0.4 | 3.35
ZDIVO Z CDm | Půdorys 1.NP | ZDIVO Z CDm 0.125 m | 1 | ZDIVO Z CDm | A | 1402HWa0798464065 | m3 | Celá stěna | Stávající | Zednické práce | ZDIVO Z CDm | yes | 1402Stě0798464066 | m3 | Stěna | 0 | 0.125 | 4.02 | 4.02 | 0.503 | 1.2 | 0.503 | 0.15 | 3.35
ZELEZOBETONOVÁ KCE | Půdorys 1.NP | ZELEZOBETONOVÁ KCE 0.15 m |  | ZELEZOBETONOVÁ KCE | A | 1402HWa0798464343 | m3 | Celá stěna | Stávající | Betonářské práce | ZELEZOBETONOVÁ KCE |  | 1402Stě0798464357 | m3 | Stěna | 0 | 0.15 | 0.599 | 0.599 | 0.09 | 1.05 | 0.09 | 0.158 | 0.57
ZELEZOBETONOVÁ KCE | Půdorys 1.NP | ZELEZOBETONOVÁ KCE 0.15 m |  | ZELEZOBETONOVÁ KCE | A | 1402HWa0798464351 | m3 | Celá stěna | Stávající | Betonářské práce | ZELEZOBETONOVÁ KCE |  | 1402Stě0798464355 | m3 | Stěna | 0 | 0.15 | 0.456 | 0.456 | 0.068 | 0.8 | 0.068 | 0.12 | 0.57
ZELEZOBETONOVÁ KCE | Půdorys 1.NP | ZELEZOBETONOVÁ KCE 0.15 m |  | ZELEZOBETONOVÁ KCE | A | 1402HWa0798464347 | m3 | Celá stěna | Stávající | Betonářské práce | ZELEZOBETONOVÁ KCE |  | 1402Stě0798464350 | m3 | Stěna | 0 | 0.15 | 0.456 | 0.456 | 0.068 | 0.8 | 0.068 | 0.12 | 0.57
ZELEZOBETONOVÁ KCE | Půdorys 1.NP | ZELEZOBETONOVÁ KCE 0.15 m |  | ZELEZOBETONOVÁ KCE | A | 1402HWa0798464345 | m3 | Celá stěna | Stávající | Betonářské práce | ZELEZOBETONOVÁ KCE |  | 1402Stě0798464356 | m3 | Stěna | 0 | 0.15 | 0.599 | 0.599 | 0.09 | 1.05 | 0.09 | 0.158 | 0.57
ZELEZOBETONOVÁ KCE | Půdorys 1.NP | ZELEZOBETONOVÁ KCE 0.3 m | 1 | ZELEZOBETONOVÁ KCE | A | 1402HWa0798441528 | m3 | Celá stěna | Stávající | Betonářské práce | ZELEZOBETONOVÁ KCE | no | 1402Stě0798441529 | m3 | Stěna | 0 | 0.3 | 4.5 | 4.5 | 1.35 | 1.25 | 1.35 | 0.375 | 3.6
ZELEZOBETONOVÁ KCE | Půdorys 1.NP | ZELEZOBETONOVÁ KCE 0.3 m | 1 | ZELEZOBETONOVÁ KCE | A | 1402HWa0798441242 | m3 | Celá stěna | Stávající | Betonářské práce | ZELEZOBETONOVÁ KCE | no | 1402Stě0798441243 | m3 | Stěna | 0 | 0.3 | 2.7 | 2.7 | 0.81 | 0.75 | 0.81 | 0.225 | 3.6
ZELEZOBETONOVÁ KCE | Půdorys 1.NP | ZELEZOBETONOVÁ KCE 0.25 m | 1 | ZELEZOBETONOVÁ KCE | A | 1402HWa0798467390 | m3 | Celá stěna | Stávající | Betonářské práce | ZELEZOBETONOVÁ KCE | no | 1402Stě0798467398 | m3 | Stěna | 0 | 0.25 | 13.14 | 9.9 | 3.285 | 3.65 | 2.475 | 0.912 | 3.6
ZELEZOBETONOVÁ KCE | Půdorys 1.NP | ZELEZOBETONOVÁ KCE 0.25 m, MINERÁLNÍ VATA 0.12 m |  | ZELEZOBETONOVÁ KCE | A | 1402HWa0798460799 | m3 | Celá stěna | Stávající | Betonářské práce | ZELEZOBETONOVÁ KCE | no | 1402Stě0798460877 | m3 | Stěna | 0 | 0.37 | 77.148 | 57.708 | 28.288 | 21.43 | 21.095 | 7.929 | 3.6 | NEMSOK - Object Layer Attributes #2, 2D interakce: yes; Object Layer Attributes #2, Status: Stávající; Object Layer Attributes #2, Práce: Zateplovací systémy; Object Layer Attributes #2, Materiál: MINERÁLNÍ VATA; Object Layer Attributes #2, Allright_Stavebni_dil_ID: 1402Stě0798460876; Object Layer Attributes #2, Jednotka: m2; Object Layer Attributes #2, Název_objektu: Stěna; Object Layer Attributes #2, Staticky nosná konstrukce: no
ZELEZOBETONOVÁ KCE | Půdorys 1.NP | ZELEZOBETONOVÁ KCE 0.15 m |  | ZELEZOBETONOVÁ KCE | A | 1402HWa0798464176 | m3 | Celá stěna | Stávající | Betonářské práce | ZELEZOBETONOVÁ KCE | no | 1402Stě0798464177 | m3 | Stěna | 0 | 0.15 | 0.563 | 0.563 | 0.084 | 0.75 | 0.084 | 0.112 | 0.75
ZELEZOBETONOVÁ KCE | Půdorys 1.NP | ZELEZOBETONOVÁ KCE 0.15 m |  | ZELEZOBETONOVÁ KCE | A | 1402HWa0798464165 | m3 | Celá stěna | Stávající | Betonářské práce | ZELEZOBETONOVÁ KCE | no | 1402Stě0798464166 | m3 | Stěna | 0 | 0.15 | 0.675 | 0.675 | 0.101 | 0.9 | 0.101 | 0.135 | 0.75
ZELEZOBETONOVÁ KCE | Půdorys 1.NP | ZELEZOBETONOVÁ KCE 0.15 m |  | ZELEZOBETONOVÁ KCE | A | 1402HWa0798464152 | m3 | Celá stěna | Stávající | Betonářské práce | ZELEZOBETONOVÁ KCE | no | 1402Stě0798464153 | m3 | Stěna | 0 | 0.15 | 0.675 | 0.675 | 0.101 | 0.9 | 0.101 | 0.135 | 0.75
ZELEZOBETONOVÁ KCE | Půdorys 1.NP | ZELEZOBETONOVÁ KCE 0.15 m |  | ZELEZOBETONOVÁ KCE | A | 1402HWa0798464195 | m3 | Celá stěna | Stávající | Betonářské práce | ZELEZOBETONOVÁ KCE | no | 1402Stě0798464196 | m3 | Stěna | 0 | 0.15 | 0.788 | 0.788 | 0.118 | 1.05 | 0.118 | 0.157 | 0.75
YTONG 250 | Půdorys 1.NP | YTONG 250 0.25 m, MINERÁLNÍ VATA 0.12 m |  | YTONG 250 | REI 180 | 1414HWa0000000004 | m3 | Celá stěna | Nový | Zednické práce | YTONG 250 | no | 1414Stě0000000005 | m3 | Stěna | 0.637 | 0.37 | 3.24 | 3.24 | 1.199 | 1.8 | 1.199 | 0.666 | 1.8 | NEMSOK - Object Layer Attributes #2, 2D interakce: yes; Object Layer Attributes #2, Status: Nový; Object Layer Attributes #2, Práce: Zateplovací systémy; Object Layer Attributes #2, Materiál: MINERÁLNÍ VATA; Object Layer Attributes #2, Allright_Stavebni_dil_ID: 1414Stě0000000033; Object Layer Attributes #2, Jednotka: m3; Object Layer Attributes #2, Název_objektu: Stěna; Object Layer Attributes #1, Kód prvku: SN06.03.0001; Object Layer Attributes #1, Funkce: Ne; Object Layer Attributes #1, U-hodnota: 0.429; Object Layer Attributes #1, Podlaží: 1.NP; Object Layer Attributes #1, Neprůzvučnost: 43 dB; Object Layer Attributes #1, Požární odolnost: REI 180; Object Layer Attributes #1, Pevnost zdiva: 2,32 N/mm2; Object Layer Attributes #1, Funkce (venkovní): Ano; Pset_WallCommon - AcousticRating: 47 dB
YTONG 250 | Půdorys 1.NP | YTONG 250 0.25 m |  | YTONG 250 | REI 180 | 1414HWa0000000010 | m3 | Celá stěna | Nový | Zednické práce | YTONG 250 | no | 1414Stě0000000011 | m3 | Stěna | 0.637 | 0.25 | 3.24 | 3.24 | 0.81 | 1.8 | 0.81 | 0.45 | 1.8 | Pset_WallCommon - AcousticRating: 47 dB; NEMSOK - Object Layer Attributes #1, Kód prvku: SN06.03.0001; Object Layer Attributes #1, Funkce: Ne; Object Layer Attributes #1, U-hodnota: 0.429; Object Layer Attributes #1, Podlaží: 1.NP; Object Layer Attributes #1, Neprůzvučnost: 43 dB; Object Layer Attributes #1, Požární odolnost: REI 180; Object Layer Attributes #1, Pevnost zdiva: 2,32 N/mm2; Object Layer Attributes #1, Funkce (venkovní): Ne
MINERÁLNÍ VATA | Půdorys 1.NP | MINERÁLNÍ VATA 0.12 m |  | MINERÁLNÍ VATA | A | 1414HWa0000000016 | m3 | Celá stěna | Nový | Zateplovací systémy | MINERÁLNÍ VATA |  | 1414Stě0000000017 | m3 | Stěna | 0 | 0.12 | 2.1 | 2.1 | 0.252 | 0.6 | 0.252 | 0.072 | 3.5 | Pset_WallCommon - LoadBearing: no; NEMSOK - Kód prvku: TI06.03.0003; Způsob spojení vrstev: Lepený + mechanicky kotvený; Součinitel prostupu tepla: 0.036; Součinitel difúzního odporu: 1
PÓROBETONOVÉ ZDIVO | Půdorys 2.NP | PÓROBETONOVÉ ZDIVO 0.1 m |  | PÓROBETONOVÉ ZDIVO | EI 120 | 1502HWa0000000041 | m3 | Celá stěna | Stávající | Zednické práce | PÓROBETONOVÉ ZDIVO |  | 1502Stě0000000751 | m2 | Stěna | 1.111 | 0.1 | 10.72 | 6.76 | 1.072 | 3.2 | 0.676 | 0.32 | 3.35 | Pset_WallCommon - AcousticRating: 37 dB
ZDIVO Z CDm | Půdorys 2.NP | ZDIVO Z CDm 0.125 m | 1 | ZDIVO Z CDm | A | 1502HWa0000000068 | m3 | Celá stěna | Stávající | Zednické práce | ZDIVO Z CDm | yes | 1502Stě0000000926 | m3 | Stěna | 0 | 0.125 | 5.192 | 5.193 | 0.649 | 1.55 | 0.649 | 0.194 | 3.35
ZELEZOBETONOVÁ KCE | Půdorys 2.NP | ZELEZOBETONOVÁ KCE 0.2 m | 1 | ZELEZOBETONOVÁ KCE | A | 1502HWa0000000070 | m3 | Celá stěna | Stávající | Betonářské práce | ZELEZOBETONOVÁ KCE |  | 1502Stě0000001015 | m3 | Stěna | 0 | 0.2 | 7.956 | 7.956 | 1.591 | 2.375 | 1.591 | 0.475 | 3.35
PÓROBETONOVÉ ZDIVO | Půdorys 2.NP | PÓROBETONOVÉ ZDIVO 0.1 m |  | PÓROBETONOVÉ ZDIVO | EI 120 | 1502HWa0000000090 | m3 | Celá stěna | Stávající | Zednické práce | PÓROBETONOVÉ ZDIVO |  | 1502Stě0000000972 | m2 | Stěna | 1.111 | 0.1 | 3.35 | 3.35 | 0.335 | 1 | 0.335 | 0.1 | 3.35 | Pset_WallCommon - AcousticRating: 37 dB
PÓROBETONOVÉ ZDIVO | Půdorys 2.NP | PÓROBETONOVÉ ZDIVO 0.1 m |  | PÓROBETONOVÉ ZDIVO | EI 120 | 1502HWa0000000105 | m3 | Celá stěna | Stávající | Zednické práce | PÓROBETONOVÉ ZDIVO |  | 1502Stě0000000987 | m2 | Stěna | 1.111 | 0.1 | 10.72 | 6.76 | 1.072 | 3.2 | 0.676 | 0.32 | 3.35 | Pset_WallCommon - AcousticRating: 37 dB
ZELEZOBETONOVÁ KCE | Půdorys 2.NP | ZELEZOBETONOVÁ KCE 0.2 m | 1 | ZELEZOBETONOVÁ KCE | A | 1502HWa0000000132 | m3 | Celá stěna | Stávající | Betonářské práce | ZELEZOBETONOVÁ KCE |  | 1502Stě0000001598 | m3 | Stěna | 0 | 0.2 | 7.956 | 7.956 | 1.591 | 2.375 | 1.591 | 0.475 | 3.35
PÓROBETONOVÉ ZDIVO | Půdorys 2.NP | PÓROBETONOVÉ ZDIVO 0.1 m | 1 | PÓROBETONOVÉ ZDIVO | EI 120 | 1502HWa0000000134 | m3 | Celá stěna | Stávající | Zednické práce | PÓROBETONOVÉ ZDIVO |  | 1502Stě0000001600 | m2 | Stěna | 1.111 | 0.1 | 7.956 | 7.956 | 0.796 | 2.375 | 0.796 | 0.237 | 3.35 | Pset_WallCommon - AcousticRating: 37 dB
ZDIVO Z CDm | Půdorys 2.NP | ZDIVO Z CDm 0.125 m | 1 | ZDIVO Z CDm | A | 1502HWa0000000146 | m3 | Celá stěna | Stávající | Zednické práce | ZDIVO Z CDm | yes | 1502Stě0000000509 | m3 | Stěna | 0 | 0.125 | 5.192 | 5.193 | 0.649 | 1.55 | 0.649 | 0.194 | 3.35
PÓROBETONOVÉ ZDIVO | Půdorys 2.NP | PÓROBETONOVÉ ZDIVO 0.1 m |  | PÓROBETONOVÉ ZDIVO | EI 120 | 1502HWa0000000169 | m3 | Celá stěna | Stávající | Zednické práce | PÓROBETONOVÉ ZDIVO |  | 1502Stě0000002296 | m2 | Stěna | 1.111 | 0.1 | 10.72 | 6.76 | 1.072 | 3.2 | 0.676 | 0.32 | 3.35 | Pset_WallCommon - AcousticRating: 37 dB
PÓROBETONOVÉ ZDIVO | Půdorys 2.NP | PÓROBETONOVÉ ZDIVO 0.1 m | 1 | PÓROBETONOVÉ ZDIVO | EI 120 | 1502HWa0000000948 | m3 | Celá stěna | Stávající | Zednické práce | PÓROBETONOVÉ ZDIVO |  | 1502Stě0000001018 | m2 | Stěna | 1.111 | 0.1 | 7.956 | 7.956 | 0.796 | 2.375 | 0.796 | 0.238 | 3.35 | Pset_WallCommon - AcousticRating: 37 dB
PÓROBETONOVÉ ZDIVO | Půdorys 2.NP | PÓROBETONOVÉ ZDIVO 0.1 m |  | PÓROBETONOVÉ ZDIVO | EI 120 | 1502HWa0000003687 | m3 | Celá stěna | Stávající | Zednické práce | PÓROBETONOVÉ ZDIVO |  | 1502Stě0000003697 | m2 | Stěna | 1.111 | 0.1 | 10.72 | 6.76 | 1.072 | 3.2 | 0.676 | 0.32 | 3.35 | Pset_WallCommon - AcousticRating: 37 dB
PÓROBETONOVÉ ZDIVO | Půdorys 2.NP | PÓROBETONOVÉ ZDIVO 0.1 m |  | PÓROBETONOVÉ ZDIVO | EI 120 | 1502HWa0000003727 | m3 | Celá stěna | Stávající | Zednické práce | PÓROBETONOVÉ ZDIVO |  | 1502Stě0000003737 | m2 | Stěna | 1.111 | 0.1 | 10.72 | 6.76 | 1.072 | 3.2 | 0.676 | 0.32 | 3.35 | Pset_WallCommon - AcousticRating: 37 dB
PÓROBETONOVÉ ZDIVO | Půdorys 2.NP | PÓROBETONOVÉ ZDIVO 0.1 m |  | PÓROBETONOVÉ ZDIVO | EI 120 | 1502HWa0000003767 | m3 | Celá stěna | Stávající | Zednické práce | PÓROBETONOVÉ ZDIVO |  | 1502Stě0000003777 | m2 | Stěna | 1.111 | 0.1 | 10.72 | 6.76 | 1.072 | 3.2 | 0.676 | 0.32 | 3.35 | Pset_WallCommon - AcousticRating: 37 dB
PÓROBETONOVÉ ZDIVO | Půdorys 2.NP | PÓROBETONOVÉ ZDIVO |  | PÓROBETONOVÉ ZDIVO | EI 120 | 1502HWa0000000166 | m3 | Celá stěna | Stávající | Zednické práce | PÓROBETONOVÉ ZDIVO |  | 1502Stě0000002299 | m2 | Stěna | 1.111 | 0.1 | 23.785 | 15.865 | 2.379 | 7.1 | 1.587 | 0.71 | 3.35 | Pset_WallCommon - AcousticRating: 37 dB
ZELEZOBETONOVÁ KCE | Půdorys 2.NP | ZELEZOBETONOVÁ KCE 0.25 m, MINERÁLNÍ VATA 0.12 m |  | ZELEZOBETONOVÁ KCE | A | 1502HWa0000000004 | m3 | Celá stěna | Stávající | Betonářské práce | ZELEZOBETONOVÁ KCE | no | 1502Stě0000000740 | m3 | Stěna | 0 | 0.37 | 42.12 | 32.4 | 13.24 | 11.64 | 9.967 | 4.315 | 3.6 | NEMSOK - Object Layer Attributes #2, 2D interakce: yes; Object Layer Attributes #2, Status: Stávající; Object Layer Attributes #2, Práce: Zateplovací systémy; Object Layer Attributes #2, Materiál: MINERÁLNÍ VATA; Object Layer Attributes #2, Allright_Stavebni_dil_ID: 1502Stě0000000734; Object Layer Attributes #2, Jednotka: m2; Object Layer Attributes #2, Název_objektu: Stěna; Object Layer Attributes #2, Staticky nosná konstrukce: no
ZELEZOBETONOVÁ KCE | Půdorys 2.NP | ZELEZOBETONOVÁ KCE 0.3 m, MINERÁLNÍ VATA 0.12 m | 1 | ZELEZOBETONOVÁ KCE | A | 1502HWa0000003607 | m3 | Celá stěna | Stávající | Betonářské práce | ZELEZOBETONOVÁ KCE | no | 1502Stě0000003609 | m3 | Stěna | 0 | 0.42 | 2.7 | 2.7 | 0.957 | 0.69 | 0.957 | 0.301 | 3.6 | NEMSOK - Object Layer Attributes #2, 2D interakce: yes; Object Layer Attributes #2, Status: Stávající; Object Layer Attributes #2, Práce: Zateplovací systémy; Object Layer Attributes #2, Materiál: MINERÁLNÍ VATA; Object Layer Attributes #2, Allright_Stavebni_dil_ID: 1502Stě0000003610; Object Layer Attributes #2, Jednotka: m2; Object Layer Attributes #2, Název_objektu: Stěna; Object Layer Attributes #2, Staticky nosná konstrukce: no
ZELEZOBETONOVÁ KCE | Půdorys 2.NP | MINERÁLNÍ VATA 0.12 m |  | ZELEZOBETONOVÁ KCE | A | 1502HWa0000003605 | m3 | Celá stěna | Stávající | Zateplovací systémy | MINERÁLNÍ VATA | no | 1502Stě0000003611 | m2 | Stěna | 0 | 0.12 | 0.332 | 0.332 | 0.04 | 0.17 | 0.04 | 0.02 | 1.95
ZELEZOBETONOVÁ KCE | Půdorys 2.NP | ZELEZOBETONOVÁ KCE 0.3 m, MINERÁLNÍ VATA 0.12 m |  | ZELEZOBETONOVÁ KCE | A | 1502HWa0000000200 | m3 | Celá stěna | Stávající | Betonářské práce | ZELEZOBETONOVÁ KCE | no | 1502Stě0000001602 | m3 | Stěna | 0 | 0.42 | 4.5 | 4.5 | 1.642 | 1.25 | 1.642 | 0.525 | 3.6 | NEMSOK - Object Layer Attributes #2, 2D interakce: yes; Object Layer Attributes #2, Status: Stávající; Object Layer Attributes #2, Práce: Zateplovací systémy; Object Layer Attributes #2, Materiál: MINERÁLNÍ VATA; Object Layer Attributes #2, Allright_Stavebni_dil_ID: 1502Stě0000002319; Object Layer Attributes #2, Jednotka: m2; Object Layer Attributes #2, Název_objektu: Stěna; Object Layer Attributes #2, Staticky nosná konstrukce: no
ZELEZOBETONOVÁ KCE | Půdorys 2.NP | ZELEZOBETONOVÁ KCE 0.3 m, MINERÁLNÍ VATA 0.12 m |  | ZELEZOBETONOVÁ KCE | A | 1502HWa0000000203 | m3 | Celá stěna | Stávající | Betonářské práce | ZELEZOBETONOVÁ KCE | no | 1502Stě0000002313 | m3 | Stěna | 0 | 0.42 | 2.7 | 2.7 | 1.007 | 0.795 | 1.007 | 0.326 | 3.6 | NEMSOK - Object Layer Attributes #2, 2D interakce: yes; Object Layer Attributes #2, Status: Stávající; Object Layer Attributes #2, Práce: Zateplovací systémy; Object Layer Attributes #2, Materiál: MINERÁLNÍ VATA; Object Layer Attributes #2, Allright_Stavebni_dil_ID: 1502Stě0000002321; Object Layer Attributes #2, Jednotka: m2; Object Layer Attributes #2, Název_objektu: Stěna; Object Layer Attributes #2, Staticky nosná konstrukce: no
ZELEZOBETONOVÁ KCE | Půdorys 2.NP | MINERÁLNÍ VATA 0.12 m |  | ZELEZOBETONOVÁ KCE | A | 1502HWa0000000144 | m3 | Celá stěna | Stávající | Zateplovací systémy | MINERÁLNÍ VATA | no | 1502Stě0000002315 | m2 | Stěna | 0 | 0.12 | 0.332 | 0.332 | 0.04 | 0.17 | 0.04 | 0.02 | 1.95
ZELEZOBETONOVÁ KCE | Půdorys 2.NP | ZELEZOBETONOVÁ KCE 0.25 m, MINERÁLNÍ VATA 0.12 m |  | ZELEZOBETONOVÁ KCE | A | 1502HWa0000004618 | m3 | Celá stěna | Stávající | Betonářské práce | ZELEZOBETONOVÁ KCE | no | 1502Stě0000004659 | m3 | Stěna | 0 | 0.37 | 9.72 | 6.48 | 3.545 | 2.64 | 2.346 | 0.985 | 3.6 | NEMSOK - Object Layer Attributes #2, 2D interakce: yes; Object Layer Attributes #2, Status: Stávající; Object Layer Attributes #2, Práce: Zateplovací systémy; Object Layer Attributes #2, Materiál: MINERÁLNÍ VATA; Object Layer Attributes #2, Allright_Stavebni_dil_ID: 1502Stě0000004658; Object Layer Attributes #2, Jednotka: m2; Object Layer Attributes #2, Název_objektu: Stěna; Object Layer Attributes #2, Staticky nosná konstrukce: no
ZELEZOBETONOVÁ KCE | Půdorys 2.NP | MINERÁLNÍ VATA 0.12 m |  | ZELEZOBETONOVÁ KCE | A | 1502HWa0000000006 | m3 | Celá stěna | Stávající | Zateplovací systémy | MINERÁLNÍ VATA | no | 1502Stě0000000538 | m2 | Stěna | 0 | 0.12 | 0.612 | 0.612 | 0.073 | 0.17 | 0.073 | 0.02 | 3.6
ZELEZOBETONOVÁ KCE | Půdorys 2.NP | ZELEZOBETONOVÁ KCE 0.3 m, MINERÁLNÍ VATA 0.12 m |  | ZELEZOBETONOVÁ KCE | A | 1502HWa0000000126 | m3 | Celá stěna | Stávající | Betonářské práce | ZELEZOBETONOVÁ KCE | no | 1502Stě0000000501 | m3 | Stěna | 0 | 0.42 | 2.7 | 2.7 | 1.082 | 0.69 | 1.082 | 0.301 | 3.6 | NEMSOK - Object Layer Attributes #2, 2D interakce: yes; Object Layer Attributes #2, Status: Stávající; Object Layer Attributes #2, Práce: Zateplovací systémy; Object Layer Attributes #2, Materiál: MINERÁLNÍ VATA; Object Layer Attributes #2, Allright_Stavebni_dil_ID: 1502Stě0000000532; Object Layer Attributes #2, Jednotka: m2; Object Layer Attributes #2, Název_objektu: Stěna; Object Layer Attributes #2, Staticky nosná konstrukce: no
ZELEZOBETONOVÁ KCE | Půdorys 2.NP | ZELEZOBETONOVÁ KCE 0.3 m, MINERÁLNÍ VATA 0.12 m |  | ZELEZOBETONOVÁ KCE | A | 1502HWa0000000128 | m3 | Celá stěna | Stávající | Betonářské práce | ZELEZOBETONOVÁ KCE | no | 1502Stě0000000503 | m3 | Stěna | 0 | 0.42 | 4.5 | 4.5 | 1.89 | 1.25 | 1.89 | 0.525 | 3.6 | NEMSOK - Object Layer Attributes #2, 2D interakce: yes; Object Layer Attributes #2, Status: Stávající; Object Layer Attributes #2, Práce: Zateplovací systémy; Object Layer Attributes #2, Materiál: MINERÁLNÍ VATA; Object Layer Attributes #2, Allright_Stavebni_dil_ID: 1502Stě0000000534; Object Layer Attributes #2, Jednotka: m2; Object Layer Attributes #2, Název_objektu: Stěna; Object Layer Attributes #2, Staticky nosná konstrukce: no
ZELEZOBETONOVÁ KCE | Půdorys 2.NP | ZELEZOBETONOVÁ KCE 0.3 m, MINERÁLNÍ VATA 0.12 m |  | ZELEZOBETONOVÁ KCE | A | 1502HWa0000000124 | m3 | Celá stěna | Stávající | Betonářské práce | ZELEZOBETONOVÁ KCE | no | 1502Stě0000000951 | m3 | Stěna | 0 | 0.42 | 2.952 | 2.952 | 1.11 | 0.76 | 1.11 | 0.308 | 3.6 | NEMSOK - Object Layer Attributes #2, 2D interakce: yes; Object Layer Attributes #2, Status: Stávající; Object Layer Attributes #2, Práce: Zateplovací systémy; Object Layer Attributes #2, Materiál: MINERÁLNÍ VATA; Object Layer Attributes #2, Allright_Stavebni_dil_ID: 1502Stě0000000536; Object Layer Attributes #2, Jednotka: m2; Object Layer Attributes #2, Název_objektu: Stěna; Object Layer Attributes #2, Staticky nosná konstrukce: no
ZELEZOBETONOVÁ KCE | Půdorys 2.NP | MINERÁLNÍ VATA 0.12 m |  | ZELEZOBETONOVÁ KCE | A | 1502HWa0000000056 | m3 | Celá stěna | Stávající | Zateplovací systémy | MINERÁLNÍ VATA | no | 1502Stě0000001131 | m2 | Stěna | 0 | 0.12 | 0.612 | 0.612 | 0.073 | 0.17 | 0.073 | 0.02 | 3.6
ZELEZOBETONOVÁ KCE | Půdorys 2.NP | ZELEZOBETONOVÁ KCE 0.25 m, MINERÁLNÍ VATA 0.12 m |  | ZELEZOBETONOVÁ KCE | A | 1502HWa0000000066 | m3 | Celá stěna | Stávající | Betonářské práce | ZELEZOBETONOVÁ KCE | no | 1502Stě0000001127 | m3 | Stěna | 0 | 0.37 | 17.28 | 14.04 | 6.342 | 4.74 | 5.143 | 1.762 | 3.6 | NEMSOK - Object Layer Attributes #2, 2D interakce: yes; Object Layer Attributes #2, Status: Stávající; Object Layer Attributes #2, Práce: Zateplovací systémy; Object Layer Attributes #2, Materiál: MINERÁLNÍ VATA; Object Layer Attributes #2, Allright_Stavebni_dil_ID: 1502Stě0000001173; Object Layer Attributes #2, Jednotka: m2; Object Layer Attributes #2, Název_objektu: Stěna; Object Layer Attributes #2, Staticky nosná konstrukce: no
ZELEZOBETONOVÁ KCE | Půdorys 2.NP | ZELEZOBETONOVÁ KCE |  | ZELEZOBETONOVÁ KCE | A | 1502HWa0000005963 | m3 | Celá stěna | Stávající | Betonářské práce | ZELEZOBETONOVÁ KCE | no | 1502Stě0000005986 | m3 | Stěna | 0 | 0.37 | 13.14 | 9.9 | 4.123 | 3.615 | 3.027 | 1.342 | 3.6 | NEMSOK - Object Layer Attributes #2, 2D interakce: yes; Object Layer Attributes #2, Status: Stávající; Object Layer Attributes #2, Práce: Zateplovací systémy; Object Layer Attributes #2, Materiál: MINERÁLNÍ VATA; Object Layer Attributes #2, Allright_Stavebni_dil_ID: 1502Stě0000005985; Object Layer Attributes #2, Jednotka: m2; Object Layer Attributes #2, Název_objektu: Stěna; Object Layer Attributes #2, Staticky nosná konstrukce: no
ZELEZOBETONOVÁ KCE | Půdorys 2.NP | ZELEZOBETONOVÁ KCE 0.25 m, MINERÁLNÍ VATA 0.12 m |  | ZELEZOBETONOVÁ KCE | A | 1502HWa0000001460 | m3 | Celá stěna | Stávající | Betonářské práce | ZELEZOBETONOVÁ KCE | no | 1502Stě0000002251 | m3 | Stěna | 0 | 0.37 | 28.8 | 22.746 | 10.656 | 8 | 8.258 | 2.96 | 3.6 | NEMSOK - Object Layer Attributes #2, 2D interakce: yes; Object Layer Attributes #2, Status: Stávající; Object Layer Attributes #2, Práce: Zateplovací systémy; Object Layer Attributes #2, Materiál: MINERÁLNÍ VATA; Object Layer Attributes #2, Allright_Stavebni_dil_ID: 1502Stě0000002221; Object Layer Attributes #2, Jednotka: m2; Object Layer Attributes #2, Název_objektu: Stěna; Object Layer Attributes #2, Staticky nosná konstrukce: no
MINERÁLNÍ VATA | Půdorys 2.NP | MINERÁLNÍ VATA 0.12 m |  | MINERÁLNÍ VATA | A | 1514HWa0000000043 | m3 | Celá stěna | Nový | Zateplovací systémy | MINERÁLNÍ VATA | no | 1514Stě0000000044 | m3 | Stěna | 0 | 0.12 | 0.99 | 0.99 | 0.119 | 0.6 | 0.119 | 0.072 | 1.65 | NEMSOK - Object Layer Attributes #1, Kód prvku: TI06.04.3001; Systém kotvení: -; Object Layer Attributes #1, Systém kotvení: -; Object Layer Attributes #1, Součinitel prostupu tepla: 0.036; Object Layer Attributes #1, Součinitel difúzního odporu: 1; Object Layer Attributes #1, Způsob spojení vrstev: Lepený + mechanicky kotvený
MINERÁLNÍ VATA | Půdorys 2.NP | MINERÁLNÍ VATA 0.12 m |  | MINERÁLNÍ VATA | A | 1514HWa0000000048 | m3 | Celá stěna | Nový | Zateplovací systémy | MINERÁLNÍ VATA | no | 1514Stě0000000049 | m3 | Stěna | 0 | 0.12 | 1.758 | 0.858 | 0.211 | 2.93 | 0.103 | 0.352 | 0.6 | NEMSOK - Object Layer Attributes #1, Kód prvku: TI06.04.3002; Systém kotvení: -; Object Layer Attributes #1, Systém kotvení: -; Object Layer Attributes #1, Součinitel prostupu tepla: 0.036; Object Layer Attributes #1, Součinitel difúzního odporu: 1; Object Layer Attributes #1, Způsob spojení vrstev: Lepený + mechanicky kotvený
MINERÁLNÍ VATA | Půdorys 2.NP | MINERÁLNÍ VATA 0.12 m |  | MINERÁLNÍ VATA | A | 1514HWa0000000060 | m3 | Celá stěna | Nový | Zateplovací systémy | MINERÁLNÍ VATA | no | 1514Stě0000000061 | m3 | Stěna | 0 | 0.12 | 0.99 | 0.99 | 0.119 | 0.6 | 0.119 | 0.072 | 1.65 | NEMSOK - Object Layer Attributes #1, Kód prvku: TI06.04.3003; Systém kotvení: -; Object Layer Attributes #1, Systém kotvení: -; Object Layer Attributes #1, Součinitel prostupu tepla: 0.036; Object Layer Attributes #1, Součinitel difúzního odporu: 1; Object Layer Attributes #1, Způsob spojení vrstev: Lepený + mechanicky kotvený
MINERÁLNÍ VATA | Půdorys 2.NP | MINERÁLNÍ VATA 0.12 m |  | MINERÁLNÍ VATA | A | 1514HWa0000000065 | m3 | Celá stěna | Nový | Zateplovací systémy | MINERÁLNÍ VATA | no | 1514Stě0000000066 | m3 | Stěna | 0 | 0.12 | 0.102 | 0.102 | 0.012 | 0.17 | 0.012 | 0.02 | 0.6 | NEMSOK - Object Layer Attributes #1, Kód prvku: TI06.04.3004; Systém kotvení: -; Object Layer Attributes #1, Systém kotvení: -; Object Layer Attributes #1, Součinitel prostupu tepla: 0.036; Object Layer Attributes #1, Součinitel difúzního odporu: 1; Object Layer Attributes #1, Způsob spojení vrstev: Lepený + mechanicky kotvený
MINERÁLNÍ VATA | Půdorys 2.NP | MINERÁLNÍ VATA 0.12 m |  | MINERÁLNÍ VATA | A | 1514HWa0000000070 | m3 | Celá stěna | Nový | Zateplovací systémy | MINERÁLNÍ VATA | no | 1514Stě0000000071 | m3 | Stěna | 0 | 0.12 | 0.522 | 0.522 | 0.063 | 0.87 | 0.063 | 0.104 | 0.6 | NEMSOK - Object Layer Attributes #1, Kód prvku: TI06.04.3005; Systém kotvení: -; Object Layer Attributes #1, Systém kotvení: -; Object Layer Attributes #1, Součinitel prostupu tepla: 0.036; Object Layer Attributes #1, Součinitel difúzního odporu: 1; Object Layer Attributes #1, Způsob spojení vrstev: Lepený + mechanicky kotvený
MINERÁLNÍ VATA | Půdorys 2.NP | MINERÁLNÍ VATA 0.12 m |  | MINERÁLNÍ VATA | A | 1514HWa0000000081 | m3 | Celá stěna | Nový | Zateplovací systémy | MINERÁLNÍ VATA | no | 1514Stě0000000082 | m3 | Stěna | 0 | 0.12 | 0.75 | 0.75 | 0.09 | 1.25 | 0.09 | 0.15 | 0.6 | NEMSOK - Object Layer Attributes #1, Kód prvku: TI06.04.3006; Systém kotvení: -; Object Layer Attributes #1, Systém kotvení: -; Object Layer Attributes #1, Součinitel prostupu tepla: 0.036; Object Layer Attributes #1, Součinitel difúzního odporu: 1; Object Layer Attributes #1, Způsob spojení vrstev: Lepený + mechanicky kotvený
MINERÁLNÍ VATA | Půdorys 2.NP | MINERÁLNÍ VATA 0.12 m |  | MINERÁLNÍ VATA | A | 1514HWa0000000092 | m3 | Celá stěna | Nový | Zateplovací systémy | MINERÁLNÍ VATA | no | 1514Stě0000000093 | m3 | Stěna | 0 | 0.12 | 0.378 | 0.378 | 0.045 | 0.63 | 0.045 | 0.076 | 0.6 | NEMSOK - Object Layer Attributes #1, Kód prvku: TI06.04.3007; Systém kotvení: -; Object Layer Attributes #1, Systém kotvení: -; Object Layer Attributes #1, Součinitel prostupu tepla: 0.036; Object Layer Attributes #1, Součinitel difúzního odporu: 1; Object Layer Attributes #1, Způsob spojení vrstev: Lepený + mechanicky kotvený
MINERÁLNÍ VATA | Půdorys 2.NP | MINERÁLNÍ VATA 0.12 m |  | MINERÁLNÍ VATA | A | 1514HWa0000000104 | m3 | Celá stěna | Nový | Zateplovací systémy | MINERÁLNÍ VATA | no | 1514Stě0000000105 | m3 | Stěna | 0 | 0.12 | 0.102 | 0.102 | 0.012 | 0.17 | 0.012 | 0.02 | 0.6 | NEMSOK - Object Layer Attributes #1, Kód prvku: TI06.04.3008; Systém kotvení: -; Object Layer Attributes #1, Systém kotvení: -; Object Layer Attributes #1, Součinitel prostupu tepla: 0.036; Object Layer Attributes #1, Součinitel difúzního odporu: 1; Object Layer Attributes #1, Způsob spojení vrstev: Lepený + mechanicky kotvený
MINERÁLNÍ VATA | Půdorys 2.NP | MINERÁLNÍ VATA 0.12 m |  | MINERÁLNÍ VATA | A | 1514HWa0000000117 | m3 | Celá stěna | Nový | Zateplovací systémy | MINERÁLNÍ VATA | no | 1514Stě0000000118 | m3 | Stěna | 0 | 0.12 | 6.588 | 3.888 | 0.791 | 10.98 | 0.467 | 1.318 | 0.6 | NEMSOK - Object Layer Attributes #1, Kód prvku: TI06.04.3009; Systém kotvení: -; Object Layer Attributes #1, Systém kotvení: -; Object Layer Attributes #1, Součinitel prostupu tepla: 0.036; Object Layer Attributes #1, Součinitel difúzního odporu: 1; Object Layer Attributes #1, Způsob spojení vrstev: Lepený + mechanicky kotvený
VÝDŘEVA | Výkopy | VÝDŘEVA 0.07 m |  | VÝDŘEVA |  | 0851HWa0000011642 | m3 | Celá stěna | Nový | Zemní práce | VÝDŘEVA | no | 0851Stě0000011643 | m3 | Stěna |  | 0.07 | 5.04 | 5.04 | 0.353 | 1.344 | 0.353 | 0.094 | 3.75 | NEMSOK - Object Layer Attributes #1, Kód prvku: SN14.01.0001; Podlaží: stavební jáma
VÝDŘEVA | Výkopy | VÝDŘEVA 0.07 m |  | VÝDŘEVA |  | 0851HWa0000011686 | m3 | Celá stěna | Nový | Zemní práce | VÝDŘEVA | no | 0851Stě0000011687 | m3 | Stěna |  | 0.07 | 5.04 | 5.04 | 0.353 | 1.344 | 0.353 | 0.094 | 3.75 | NEMSOK - Object Layer Attributes #1, Kód prvku: SN14.01.0002; Podlaží: stavební jáma
VÝDŘEVA | Výkopy | VÝDŘEVA 0.07 m |  | VÝDŘEVA |  | 0851HWa0000011689 | m3 | Celá stěna | Nový | Zemní práce | VÝDŘEVA | no | 0851Stě0000011690 | m3 | Stěna |  | 0.07 | 5.04 | 5.04 | 0.353 | 1.344 | 0.353 | 0.094 | 3.75 | NEMSOK - Object Layer Attributes #1, Kód prvku: SN14.01.0003; Podlaží: stavební jáma
VÝDŘEVA | Výkopy | VÝDŘEVA 0.07 m |  | VÝDŘEVA |  | 0851HWa0000011692 | m3 | Celá stěna | Nový | Zemní práce | VÝDŘEVA | no | 0851Stě0000011693 | m3 | Stěna |  | 0.07 | 5.04 | 5.04 | 0.353 | 1.344 | 0.353 | 0.094 | 3.75 | NEMSOK - Object Layer Attributes #1, Kód prvku: SN14.01.0004; Podlaží: stavební jáma
VÝDŘEVA | Výkopy | VÝDŘEVA 0.07 m |  | VÝDŘEVA |  | 0851HWa0000011695 | m3 | Celá stěna | Nový | Zemní práce | VÝDŘEVA | no | 0851Stě0000011696 | m3 | Stěna |  | 0.07 | 5.04 | 5.04 | 0.353 | 1.344 | 0.353 | 0.094 | 3.75 | NEMSOK - Object Layer Attributes #1, Kód prvku: SN14.01.0005; Podlaží: stavební jáma
VÝDŘEVA | Výkopy | VÝDŘEVA 0.07 m |  | VÝDŘEVA |  | 0851HWa0000011698 | m3 | Celá stěna | Nový | Zemní práce | VÝDŘEVA | no | 0851Stě0000011699 | m3 | Stěna |  | 0.07 | 5.04 | 5.04 | 0.353 | 1.344 | 0.353 | 0.094 | 3.75 | NEMSOK - Object Layer Attributes #1, Kód prvku: SN14.01.0006; Podlaží: stavební jáma
VÝDŘEVA | Výkopy | VÝDŘEVA 0.07 m |  | VÝDŘEVA |  | 0851HWa0000011701 | m3 | Celá stěna | Nový | Zemní práce | VÝDŘEVA | no | 0851Stě0000011702 | m3 | Stěna |  | 0.07 | 5.04 | 5.04 | 0.353 | 1.344 | 0.353 | 0.094 | 3.75 | NEMSOK - Object Layer Attributes #1, Kód prvku: SN14.01.0007; Podlaží: stavební jáma
VÝDŘEVA | Výkopy | VÝDŘEVA 0.07 m |  | VÝDŘEVA |  | 0851HWa0000011704 | m3 | Celá stěna | Nový | Zemní práce | VÝDŘEVA | no | 0851Stě0000011705 | m3 | Stěna |  | 0.07 | 5.04 | 5.04 | 0.353 | 1.344 | 0.353 | 0.094 | 3.75 | NEMSOK - Object Layer Attributes #1, Kód prvku: SN14.01.0008; Podlaží: stavební jáma
VÝDŘEVA | Výkopy | VÝDŘEVA 0.07 m |  | VÝDŘEVA |  | 0851HWa0000011707 | m3 | Celá stěna | Nový | Zemní práce | VÝDŘEVA | no | 0851Stě0000011708 | m3 | Stěna |  | 0.07 | 5.04 | 5.04 | 0.353 | 1.344 | 0.353 | 0.094 | 3.75 | NEMSOK - Object Layer Attributes #1, Kód prvku: SN14.01.0009; Podlaží: stavební jáma
VÝDŘEVA | Výkopy | VÝDŘEVA 0.07 m |  | VÝDŘEVA |  | 0851HWa0000011710 | m3 | Celá stěna | Nový | Zemní práce | VÝDŘEVA | no | 0851Stě0000011711 | m3 | Stěna |  | 0.07 | 1.507 | 1.508 | 0.106 | 0.402 | 0.106 | 0.028 | 3.75 | NEMSOK - Object Layer Attributes #1, Kód prvku: SN14.01.0010; Podlaží: stavební jáma
VÝDŘEVA | Výkopy | VÝDŘEVA 0.07 m | 1 | VÝDŘEVA |  | 0851HWa0000012009 | m3 | Celá stěna | Nový | Zemní práce | VÝDŘEVA | no | 0851Stě0000012010 | m3 | Stěna |  | 0.07 | 6.424 | 6.424 | 0.45 | 1.494 | 0.45 | 0.105 | 4.3 | NEMSOK - Object Layer Attributes #1, Kód prvku: SN14.01.0011; Podlaží: stavební jáma
VÝDŘEVA | Výkopy | VÝDŘEVA 0.07 m | 1 | VÝDŘEVA |  | 0851HWa0000012014 | m3 | Celá stěna | Nový | Zemní práce | VÝDŘEVA | no | 0851Stě0000012015 | m3 | Stěna |  | 0.07 | 6.424 | 6.424 | 0.45 | 1.494 | 0.45 | 0.105 | 4.3 | NEMSOK - Object Layer Attributes #1, Kód prvku: SN14.01.0012; Podlaží: stavební jáma
VÝDŘEVA | Výkopy | VÝDŘEVA 0.07 m | 1 | VÝDŘEVA |  | 0851HWa0000012017 | m3 | Celá stěna | Nový | Zemní práce | VÝDŘEVA | no | 0851Stě0000012018 | m3 | Stěna |  | 0.07 | 6.424 | 6.424 | 0.45 | 1.494 | 0.45 | 0.105 | 4.3 | NEMSOK - Object Layer Attributes #1, Kód prvku: SN14.01.0013; Podlaží: stavební jáma
VÝDŘEVA | Výkopy | VÝDŘEVA 0.07 m | 1 | VÝDŘEVA |  | 0851HWa0000012020 | m3 | Celá stěna | Nový | Zemní práce | VÝDŘEVA | no | 0851Stě0000012021 | m3 | Stěna |  | 0.07 | 6.424 | 6.424 | 0.45 | 1.494 | 0.45 | 0.105 | 4.3 | NEMSOK - Object Layer Attributes #1, Kód prvku: SN14.01.0014; Podlaží: stavební jáma
VÝDŘEVA | Výkopy | VÝDŘEVA 0.07 m | 1 | VÝDŘEVA |  | 0851HWa0000012023 | m3 | Celá stěna | Nový | Zemní práce | VÝDŘEVA | no | 0851Stě0000012024 | m3 | Stěna |  | 0.07 | 6.424 | 6.424 | 0.45 | 1.494 | 0.45 | 0.105 | 4.3 | NEMSOK - Object Layer Attributes #1, Kód prvku: SN14.01.0015; Podlaží: stavební jáma
VÝDŘEVA | Výkopy | VÝDŘEVA 0.07 m | 1 | VÝDŘEVA |  | 0851HWa0000012026 | m3 | Celá stěna | Nový | Zemní práce | VÝDŘEVA | no | 0851Stě0000012027 | m3 | Stěna |  | 0.07 | 6.424 | 6.424 | 0.45 | 1.494 | 0.45 | 0.105 | 4.3 | NEMSOK - Object Layer Attributes #1, Kód prvku: SN14.01.0016; Podlaží: stavební jáma
VÝDŘEVA | Výkopy | VÝDŘEVA 0.07 m | 1 | VÝDŘEVA |  | 0851HWa0000012029 | m3 | Celá stěna | Nový | Zemní práce | VÝDŘEVA | no | 0851Stě0000012030 | m3 | Stěna |  | 0.07 | 6.424 | 6.424 | 0.45 | 1.494 | 0.45 | 0.105 | 4.3 | NEMSOK - Object Layer Attributes #1, Kód prvku: SN14.01.0017; Podlaží: stavební jáma
VÝDŘEVA | Výkopy | VÝDŘEVA 0.07 m | 1 | VÝDŘEVA |  | 0851HWa0000012035 | m3 | Celá stěna | Nový | Zemní práce | VÝDŘEVA | no | 0851Stě0000012036 | m3 | Stěna |  | 0.07 | 3.629 | 3.629 | 0.254 | 0.844 | 0.254 | 0.059 | 4.3 | NEMSOK - Object Layer Attributes #1, Kód prvku: SN14.01.0019; Podlaží: stavební jáma
VÝDŘEVA | Výkopy | VÝDŘEVA 0.07 m |  | VÝDŘEVA |  | 0851HWa0000012040 | m3 | Celá stěna | Nový | Zemní práce | VÝDŘEVA | no | 0851Stě0000012041 | m3 | Stěna |  | 0.07 | 4.482 | 4.482 | 0.314 | 1.494 | 0.314 | 0.105 | 3 | NEMSOK - Object Layer Attributes #1, Kód prvku: SN14.01.0020; Podlaží: stavební jáma
VÝDŘEVA | Výkopy | VÝDŘEVA 0.07 m |  | VÝDŘEVA |  | 0851HWa0000012043 | m3 | Celá stěna | Nový | Zemní práce | VÝDŘEVA | no | 0851Stě0000012044 | m3 | Stěna |  | 0.07 | 2.988 | 2.988 | 0.209 | 1.494 | 0.209 | 0.105 | 2 | NEMSOK - Object Layer Attributes #1, Kód prvku: SN14.01.0021; Podlaží: stavební jáma
VÝDŘEVA | Výkopy | VÝDŘEVA 0.07 m |  | VÝDŘEVA |  | 0851HWa0000012046 | m3 | Celá stěna | Nový | Zemní práce | VÝDŘEVA | no | 0851Stě0000012047 | m3 | Stěna |  | 0.07 | 2.241 | 2.241 | 0.157 | 1.494 | 0.157 | 0.105 | 1.5 | NEMSOK - Object Layer Attributes #1, Kód prvku: SN14.01.0022; Podlaží: stavební jáma
VÝDŘEVA | Výkopy | VÝDŘEVA 0.07 m | 1 | VÝDŘEVA |  | 0851HWa0000012061 | m3 | Celá stěna | Nový | Zemní práce | VÝDŘEVA | no | 0851Stě0000012063 | m3 | Stěna |  | 0.07 | 6.424 | 6.424 | 0.45 | 1.494 | 0.45 | 0.105 | 4.3 | NEMSOK - Object Layer Attributes #1, Kód prvku: SN14.01.0023; Podlaží: stavební jáma
VÝDŘEVA | Výkopy | VÝDŘEVA 0.07 m |  | VÝDŘEVA |  | 0851HWa0000012032 | m3 | Celá stěna | Nový | Zemní práce | VÝDŘEVA | no | 0851Stě0000012033 | m3 | Stěna |  | 0.07 | 6.424 | 6.424 | 0.45 | 1.494 | 0.45 | 0.105 | 4.3 | NEMSOK - Object Layer Attributes #1, Kód prvku: SN14.01.0018; Podlaží: stavební jáma
PERIMETR | Základy | PERIMETR 0.15 m |  | PERIMETR |  | 0881HWa0000000636 | m3 | Celá stěna | Nový | Zateplovací systémy | PERIMETR | no | 0881Stě0000000637 | m3 | Stěna |  | 0.15 | 3.785 | 3.785 | 0.568 | 7.57 | 0.568 | 1.136 | 0.5 | NEMSOK - Object Layer Attributes #1, Kód prvku: TI02.01.0001; Object Layer Attributes #1, Požární odolnost: E; Object Layer Attributes #1, Součinitel prostupu tepla: 0.034; Object Layer Attributes #1, Součinitel difúzního odporu: 40 - 100; Object Layer Attributes #1, Způsob spojení vrstev: Lepený
PERIMETR | Základy | PERIMETR 0.05 m |  | PERIMETR |  | 0881HWa0000000645 | m3 | Celá stěna | Nový | Zateplovací systémy | PERIMETR | no | 0881Stě0000000646 | m3 | Stěna |  | 0.05 | 2.525 | 2.525 | 0.126 | 5.05 | 0.126 | 0.252 | 0.5 | NEMSOK - Object Layer Attributes #1, Kód prvku: TI02.01.0002; Object Layer Attributes #1, Požární odolnost: E; Object Layer Attributes #1, Součinitel prostupu tepla: 0.034; Object Layer Attributes #1, Součinitel difúzního odporu: 40 - 100; Object Layer Attributes #1, Způsob spojení vrstev: Lepený
ZDIVO Z CDm | Půdorys 1.PP | ZDIVO Z CDm 0.5 m | 1 | ZDIVO Z CDm | A | 1352HWa0000000068 | m3 | Celá stěna | Stávající | Zednické práce | ZDIVO Z CDm | yes | 1352Stě0000001574 | m3 | Stěna | 0 | 0.5 | 15.968 | 15.969 | 7.984 | 5.45 | 7.984 | 2.725 | 2.93
ZDIVO Z CDm | Půdorys 1.PP | ZDIVO Z CDm 0.5 m | 1 | ZDIVO Z CDm | A | 1352HWa0000000070 | m3 | Celá stěna | Stávající | Zednické práce | ZDIVO Z CDm | yes | 1352Stě0000001578 | m3 | Stěna | 0 | 0.5 | 10.255 | 10.255 | 5.127 | 3.5 | 5.127 | 1.75 | 2.93
ZDIVO Z CDm | Půdorys 1.PP | ZDIVO Z CDm 0.5 m |  | ZDIVO Z CDm | A | 1352HWa0000000077 | m3 | Celá stěna | Stávající | Zednické práce | ZDIVO Z CDm | yes | 1352Stě0000001568 | m3 | Stěna | 0 | 0.5 | 14.503 | 9.122 | 7.252 | 4.95 | 4.561 | 2.475 | 2.93
ZELEZOBETONOVÁ KCE | Půdorys 1.PP | ZELEZOBETONOVÁ KCE 0.2 m | 1 | ZELEZOBETONOVÁ KCE | A | 1352HWa0000005349 | m3 | Celá stěna | Stávající | Betonářské práce | ZELEZOBETONOVÁ KCE | yes | 1352Stě0000005350 | m3 | Stěna | 0 | 0.2 | 32.489 | 32.489 | 6.498 | 8.595 | 6.498 | 1.719 | 3.78
ZELEZOBETONOVÁ KCE | Půdorys 1.PP | ZELEZOBETONOVÁ KCE 0.2 m | 1 | ZELEZOBETONOVÁ KCE | A | 1352HWa0000002482 | m3 | Celá stěna | Stávající | Betonářské práce | ZELEZOBETONOVÁ KCE | yes | 1352Stě0000002483 | m3 | Stěna | 0 | 0.2 | 10.05 | 10.05 | 2.01 | 3 | 2.01 | 0.6 | 3.35
ZDIVO Z CDm | Půdorys 1.PP | ZDIVO Z CDm 0.5 m |  | ZDIVO Z CDm | A | 1352HWa0000001433 | m3 | Celá stěna | Stávající | Zednické práce | ZDIVO Z CDm | yes | 1352Stě0000001562 | m3 | Stěna | 0 | 0.5 | 26.809 | 19.664 | 13.405 | 9.15 | 9.746 | 4.575 | 2.93
ZELEZOBETONOVÁ KCE | Půdorys 1.PP | ZELEZOBETONOVÁ KCE 0.5 m | 1 | ZELEZOBETONOVÁ KCE | A | 1352HWa0000004550 | m3 | Celá stěna | Stávající | Betonářské práce | ZELEZOBETONOVÁ KCE | no | 1352Stě0000004551 | m3 | Stěna | 0 | 0.5 | 2.544 | 2.544 | 1.272 | 0.8 | 1.272 | 0.4 | 3.18 | Pset_WallCommon - LoadBearing: yes
ZELEZOBETONOVÁ KCE | Půdorys 1.PP | ZELEZOBETONOVÁ KCE 0.3 m |  | ZELEZOBETONOVÁ KCE | A | 1352HWa0000004608 | m3 | Celá stěna | Stávající | Betonářské práce | ZELEZOBETONOVÁ KCE | no | 1352Stě0000004611 | m3 | Stěna | 0 | 0.3 | 21.45 | 21.45 | 6.435 | 6.5 | 6.435 | 1.95 | 3.3 | Pset_WallCommon - LoadBearing: yes
PÓROBETONOVÉ ZDIVO | Půdorys 1.PP | PÓROBETONOVÉ ZDIVO 0.1 m | 1 | PÓROBETONOVÉ ZDIVO | EI 120 | 1352HWa0798428020 | m3 | Celá stěna | Stávající | Zednické práce | PÓROBETONOVÉ ZDIVO |  | 1352Stě0798428021 | m2 | Stěna | 1.111 | 0.1 | 13.725 | 13.725 | 1.372 | 4.5 | 1.372 | 0.45 | 3.05 | Pset_WallCommon - AcousticRating: 37 dB
PÓROBETONOVÉ ZDIVO | Půdorys 1.PP | PÓROBETONOVÉ ZDIVO 0.1 m | 1 | PÓROBETONOVÉ ZDIVO | EI 120 | 1352HWa0798428026 | m3 | Celá stěna | Stávající | Zednické práce | PÓROBETONOVÉ ZDIVO |  | 1352Stě0798428027 | m2 | Stěna | 1.111 | 0.1 | 1.22 | 1.22 | 0.122 | 0.4 | 0.122 | 0.04 | 3.05 | Pset_WallCommon - AcousticRating: 37 dB
ZDIVO Z CDm | Půdorys 1.PP | ZDIVO Z CDm 0.125 m | 1 | ZDIVO Z CDm | A | 1352HWa0798428044 | m3 | Celá stěna | Stávající | Zednické práce | ZDIVO Z CDm | yes | 1352Stě0798428045 | m3 | Stěna | 0 | 0.125 | 1.22 | 1.22 | 0.152 | 0.4 | 0.152 | 0.05 | 3.05
ZELEZOBETONOVÁ KCE | Půdorys 1.PP | ZELEZOBETONOVÁ KCE 0.2 m |  | ZELEZOBETONOVÁ KCE | A | 1352HWa0000008509 | m3 | Celá stěna | Stávající | Betonářské práce | ZELEZOBETONOVÁ KCE | yes | 1352Stě0000008510 | m3 | Stěna | 0 | 0.2 | 6.365 | 6.365 | 1.273 | 1.9 | 1.273 | 0.38 | 3.35
ZELEZOBETONOVÁ KCE | Půdorys 1.PP | ZELEZOBETONOVÁ KCE 0.2 m |  | ZELEZOBETONOVÁ KCE | A | 1352HWa0798428315 | m3 | Celá stěna | Stávající | Betonářské práce | ZELEZOBETONOVÁ KCE | yes | 1352Stě0798428317 | m3 | Stěna | 0 | 0.2 | 6.365 | 6.365 | 1.273 | 1.9 | 1.273 | 0.38 | 3.35
ZELEZOBETONOVÁ KCE | Půdorys 1.PP | ZELEZOBETONOVÁ KCE 0.2 m | 1 | ZELEZOBETONOVÁ KCE | A | 1352HWa0000008518 | m3 | Celá stěna | Stávající | Betonářské práce | ZELEZOBETONOVÁ KCE | yes | 1352Stě0000008519 | m3 | Stěna | 0 | 0.2 | 5.092 | 5.092 | 1.018 | 1.52 | 1.018 | 0.304 | 3.35
ZELEZOBETONOVÁ KCE | Půdorys 1.PP | ZELEZOBETONOVÁ KCE 0.2 m | 1 | ZELEZOBETONOVÁ KCE | A | 1352HWa0798428342 | m3 | Celá stěna | Stávající | Betonářské práce | ZELEZOBETONOVÁ KCE | yes | 1352Stě0798428344 | m3 | Stěna | 0 | 0.2 | 5.092 | 5.092 | 1.018 | 1.52 | 1.018 | 0.304 | 3.35
ZELEZOBETONOVÁ KCE | Půdorys 1.PP | ZELEZOBETONOVÁ KCE 0.2 m | 1 | ZELEZOBETONOVÁ KCE | A | 1352HWa0000002502 | m3 | Celá stěna | Stávající | Betonářské práce | ZELEZOBETONOVÁ KCE | yes | 1352Stě0000002503 | m3 | Stěna | 0 | 0.2 | 12.06 | 12.06 | 2.412 | 3.6 | 2.412 | 0.72 | 3.35
ZDIVO Z CDm | Půdorys 1.PP | ZDIVO Z CDm 0.35 m | 1 | ZDIVO Z CDm | A | 1352HWa0798427897 | m3 | Celá stěna | Stávající | Zednické práce | ZDIVO Z CDm | yes | 1352Stě0798427898 | m3 | Stěna | 0 | 0.35 | 1.22 | 1.22 | 0.427 | 0.4 | 0.427 | 0.14 | 3.05
ZDIVO Z CDm | Půdorys 1.PP | ZDIVO Z CDm 0.35 m | 1 | ZDIVO Z CDm | A | 1352HWa0798427888 | m3 | Celá stěna | Stávající | Zednické práce | ZDIVO Z CDm | yes | 1352Stě0798427889 | m3 | Stěna | 0 | 0.35 | 1.22 | 1.22 | 0.427 | 0.4 | 0.427 | 0.14 | 3.05
ZDIVO Z CDm | Půdorys 1.PP | ZDIVO Z CDm 0.25 m | 1 | ZDIVO Z CDm | A | 1352HWa0000012841 | m3 | Celá stěna | Stávající | Zednické práce | ZDIVO Z CDm | yes | 1352Stě0000012861 | m3 | Stěna | 0 | 0.25 | 15.25 | 8.244 | 3.812 | 5 | 2.061 | 1.25 | 3.05
ZELEZOBETONOVÁ KCE | Půdorys 1.PP | ZELEZOBETONOVÁ KCE 0.2 m | 1 | ZELEZOBETONOVÁ KCE | A | 1352HWa0798428519 | m3 | Celá stěna | Stávající | Betonářské práce | ZELEZOBETONOVÁ KCE | yes | 1352Stě0798428520 | m3 | Stěna | 0 | 0.2 | 12.06 | 12.06 | 2.412 | 3.6 | 2.412 | 0.72 | 3.35
ZELEZOBETONOVÁ KCE | Půdorys 1.PP | ZELEZOBETONOVÁ KCE 0.2 m | 1 | ZELEZOBETONOVÁ KCE | A | 1352HWa0000002488 | m3 | Celá stěna | Stávající | Betonářské práce | ZELEZOBETONOVÁ KCE | yes | 1352Stě0000002489 | m3 | Stěna | 0 | 0.2 | 13.4 | 13.4 | 2.68 | 4 | 2.68 | 0.8 | 3.35
ZELEZOBETONOVÁ KCE | Půdorys 1.PP | ZELEZOBETONOVÁ KCE 0.2 m | 1 | ZELEZOBETONOVÁ KCE | A | 1352HWa0000002831 | m3 | Celá stěna | Stávající | Betonářské práce | ZELEZOBETONOVÁ KCE | yes | 1352Stě0000002832 | m3 | Stěna | 0 | 0.2 | 16.08 | 16.08 | 3.216 | 4.8 | 3.216 | 0.96 | 3.35
ZELEZOBETONOVÁ KCE | Půdorys 1.PP | ZELEZOBETONOVÁ KCE 0.2 m | 1 | ZELEZOBETONOVÁ KCE | A | 1352HWa0798428653 | m3 | Celá stěna | Stávající | Betonářské práce | ZELEZOBETONOVÁ KCE | yes | 1352Stě0798428655 | m3 | Stěna | 0 | 0.2 | 16.08 | 16.08 | 3.216 | 4.8 | 3.216 | 0.96 | 3.35
ZELEZOBETONOVÁ KCE | Půdorys 1.PP | ZELEZOBETONOVÁ KCE 0.2 m, LIGNOPOR 0.025 m |  | ZELEZOBETONOVÁ KCE | A | 1352HWa0000004021 | m3 | Celá stěna | Stávající | Betonářské práce | ZELEZOBETONOVÁ KCE | no | 1352Stě0000004022 | m3 | Stěna | 0 | 0.225 | 4.59 | 4.59 | 1.019 | 1.37 | 1.019 | 0.308 | 3.35 | NEMSOK - Object Layer Attributes #2, 2D interakce: yes; Object Layer Attributes #2, Status: Stávající; Object Layer Attributes #2, Práce: Zateplovací systémy; Object Layer Attributes #2, Materiál: LIGNOPOR; Object Layer Attributes #2, Allright_Stavebni_dil_ID: 1352Stě0000004023; Object Layer Attributes #2, Jednotka: m2; Object Layer Attributes #2, Název_objektu: Stěna; Object Layer Attributes #2, Staticky nosná konstrukce: no; Pset_WallCommon - LoadBearing: yes
ZELEZOBETONOVÁ KCE | Půdorys 1.PP | ZELEZOBETONOVÁ KCE 0.25 m, LIGNOPOR 0.025 m, PÓROBETONOVÉ ZDIVO 0.08 m | 1 | ZELEZOBETONOVÁ KCE | A | 1352HWa0000003688 | m3 | Celá stěna | Stávající | Betonářské práce | ZELEZOBETONOVÁ KCE |  | 1352Stě0000003689 | m3 | Stěna | 0 | 0.355 | 3.761 | 3.761 | 1.142 | 1.198 | 1.142 | 0.404 | 3.35 | NEMSOK - Object Layer Attributes #2, 2D interakce: yes; Object Layer Attributes #2, Status: Stávající; Object Layer Attributes #2, Práce: Zateplovací systémy; Object Layer Attributes #2, Materiál: LIGNOPOR; Object Layer Attributes #2, Allright_Stavebni_dil_ID: 1352Stě0000003690; Object Layer Attributes #2, Jednotka: m2; Object Layer Attributes #2, Název_objektu: Stěna; Object Layer Attributes #3, 2D interakce: yes; Object Layer Attributes #3, Status: Stávající; Object Layer Attributes #3, Práce: Zednické práce; Object Layer Attributes #3, Materiál: PÓROBETONOVÉ ZDIVO; Object Layer Attributes #3, Allright_Stavebni_dil_ID: 1352Stě0798431179; Object Layer Attributes #3, Jednotka: m2; Object Layer Attributes #3, Název_objektu: Stěna; Pset_WallCommon - LoadBearing: yes
ZELEZOBETONOVÁ KCE | Půdorys 1.PP | ZELEZOBETONOVÁ KCE 0.2 m, LIGNOPOR 0.025 m, PÓROBETONOVÉ ZDIVO 0.08 m | 1 | ZELEZOBETONOVÁ KCE | A | 1352HWa0000003923 | m3 | Celá stěna | Stávající | Betonářské práce | ZELEZOBETONOVÁ KCE |  | 1352Stě0000003924 | m3 | Stěna | 0 | 0.305 | 33.189 | 33.19 | 8.242 | 7.872 | 8.242 | 2.339 | 4.1 | NEMSOK - Object Layer Attributes #2, 2D interakce: yes; Object Layer Attributes #2, Status: Stávající; Object Layer Attributes #2, Práce: Zateplovací systémy; Object Layer Attributes #2, Materiál: LIGNOPOR; Object Layer Attributes #2, Allright_Stavebni_dil_ID: 1352Stě0000003925; Object Layer Attributes #2, Jednotka: m2; Object Layer Attributes #2, Název_objektu: Stěna; Object Layer Attributes #3, 2D interakce: yes; Object Layer Attributes #3, Status: Stávající; Object Layer Attributes #3, Práce: Zednické práce; Object Layer Attributes #3, Materiál: PÓROBETONOVÉ ZDIVO; Object Layer Attributes #3, Allright_Stavebni_dil_ID: 1352Stě0798431779; Object Layer Attributes #3, Jednotka: m2; Object Layer Attributes #3, Název_objektu: Stěna; Pset_WallCommon - LoadBearing: yes
ZELEZOBETONOVÁ KCE | Půdorys 1.PP | ZELEZOBETONOVÁ KCE | 1 | ZELEZOBETONOVÁ KCE | A | 1352HWa0000002506 | m3 | Celá stěna | Stávající | Betonářské práce | ZELEZOBETONOVÁ KCE |  | 1352Stě0000002507 | m3 | Stěna | 0 | 0.755 | 43.686 | 42.713 | 27.247 | 10.593 | 27.148 | 7.974 | 4.1 | NEMSOK - Object Layer Attributes #2, 2D interakce: yes; Object Layer Attributes #2, Status: Stávající; Object Layer Attributes #2, Práce: Zateplovací systémy; Object Layer Attributes #2, Materiál: LIGNOPOR; Object Layer Attributes #2, Allright_Stavebni_dil_ID: 1352Stě0000002508; Object Layer Attributes #2, Jednotka: m2; Object Layer Attributes #2, Název_objektu: Stěna; Object Layer Attributes #3, 2D interakce: yes; Object Layer Attributes #3, Status: Stávající; Object Layer Attributes #3, Práce: Zednické práce; Object Layer Attributes #3, Materiál: PÓROBETONOVÉ ZDIVO; Object Layer Attributes #3, Allright_Stavebni_dil_ID: 1352Stě0798429797; Object Layer Attributes #3, Jednotka: m2; Object Layer Attributes #3, Název_objektu: Stěna; Pset_WallCommon - LoadBearing: yes
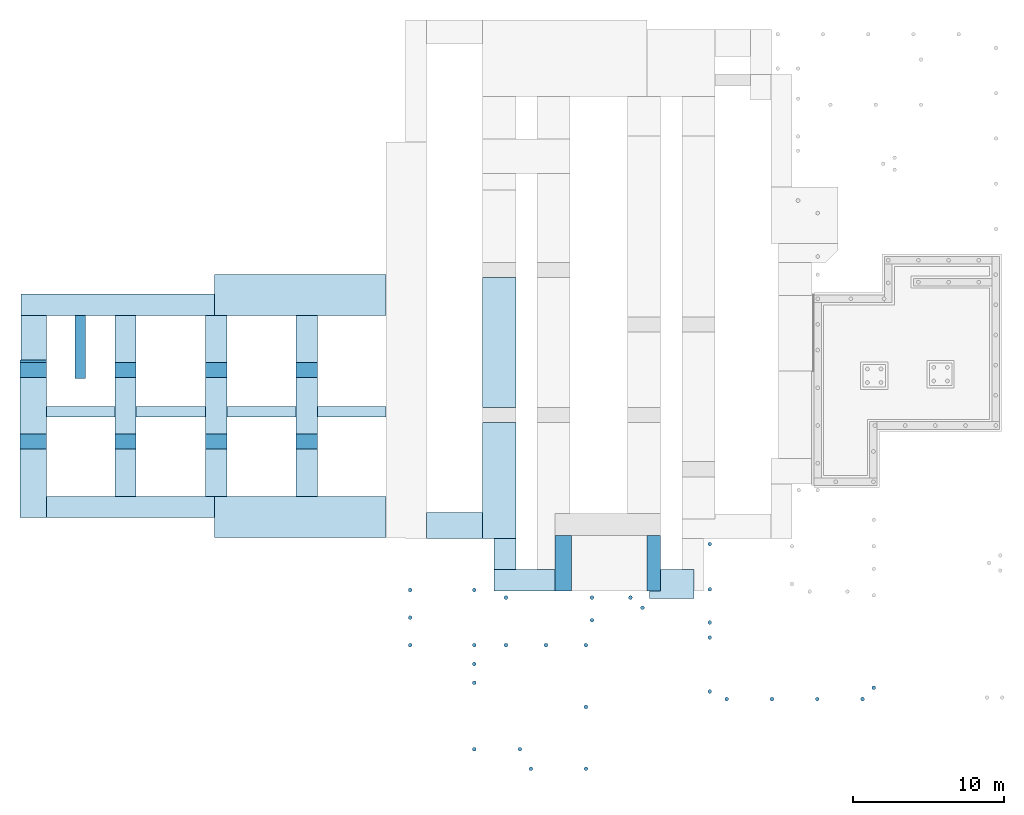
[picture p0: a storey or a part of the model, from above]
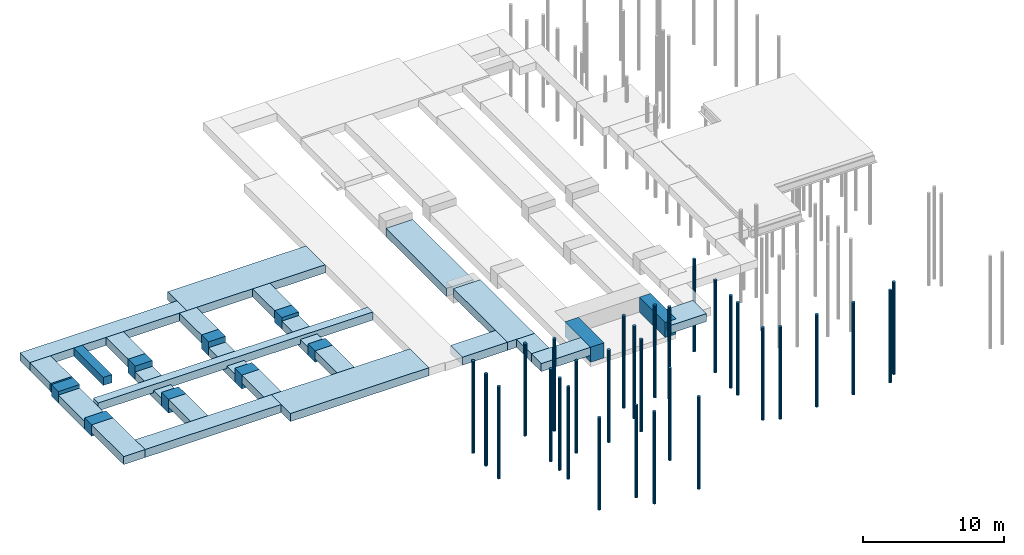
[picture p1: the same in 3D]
Properties of the parts of a building model (IFC4), part 25 of 45

# IfcWall (2385)
Name | In | Material | Faktor | Označení | Požární odolnost | Allright_Stavebni_dil_ID | Jednotka | Název_objektu | Object Layer Attributes #1, Status | Object Layer Attributes #1, Práce | Object Layer Attributes #1, Materiál | Object Layer Attributes #1, Staticky nosná konstrukce | Object Layer Attributes #1, Allright_Stavebni_dil_ID | Object Layer Attributes #1, Jednotka | Object Layer Attributes #1, Název_objektu | ThermalTransmittance (W/K/m2) | Width (m) | GrossSideArea (m2) | NetSideArea (m2) | GrossVolume (m3) | Length (m) | NetVolume (m3) | GrossFootprintArea (m2) | Height (m)
ZELEZOBETONOVÁ KCE | Půdorys 1.PP | ZELEZOBETONOVÁ KCE | 1 | ZELEZOBETONOVÁ KCE | A | 1352HWa0000002640 | m3 | Celá stěna | Stávající | Betonářské práce | ZELEZOBETONOVÁ KCE |  | 1352Stě0000002641 | m3 | Stěna | 0 | 0.755 | 15.888 | 14.307 | 7.721 | 3.537 | 7.528 | 2.247 | 4.1 | NEMSOK - Object Layer Attributes #2, 2D interakce: yes; Object Layer Attributes #2, Status: Stávající; Object Layer Attributes #2, Práce: Zateplovací systémy; Object Layer Attributes #2, Materiál: LIGNOPOR; Object Layer Attributes #2, Allright_Stavebni_dil_ID: 1352Stě0000002642; Object Layer Attributes #2, Jednotka: m2; Object Layer Attributes #2, Název_objektu: Stěna; Object Layer Attributes #3, 2D interakce: yes; Object Layer Attributes #3, Status: Stávající; Object Layer Attributes #3, Práce: Zednické práce; Object Layer Attributes #3, Materiál: PÓROBETONOVÉ ZDIVO; Object Layer Attributes #3, Allright_Stavebni_dil_ID: 1352Stě0798432908; Object Layer Attributes #3, Jednotka: m2; Object Layer Attributes #3, Název_objektu: Stěna; Pset_WallCommon - LoadBearing: yes
ZELEZOBETONOVÁ KCE | Půdorys 1.PP | PÓROBETONOVÉ ZDIVO 0.08 m | 1 | ZELEZOBETONOVÁ KCE | A | 1352HWa0798434329 | m3 | Celá stěna | Stávající | Zednické práce | PÓROBETONOVÉ ZDIVO |  | 1352Stě0798434330 | m2 | Stěna | 0 | 0.08 | 0.697 | 0.697 | 0.056 | 0.17 | 0.056 | 0.014 | 4.1 | Pset_WallCommon - LoadBearing: yes
ZELEZOBETONOVÁ KCE | Půdorys 1.PP | ZELEZOBETONOVÁ KCE 0.45 m, LIGNOPOR 0.025 m, PÓROBETONOVÉ ZDIVO 0.08 m |  | ZELEZOBETONOVÁ KCE | A | 1352HWa0000001874 | m3 | Celá stěna | Stávající | Betonářské práce | ZELEZOBETONOVÁ KCE |  | 1352Stě0000001875 | m3 | Stěna | 0 | 0.555 | 3.52 | 3.52 | 1.488 | 0.8 | 1.488 | 0.444 | 4.4 | NEMSOK - Object Layer Attributes #2, 2D interakce: yes; Object Layer Attributes #2, Status: Stávající; Object Layer Attributes #2, Práce: Zateplovací systémy; Object Layer Attributes #2, Materiál: LIGNOPOR; Object Layer Attributes #2, Allright_Stavebni_dil_ID: 1352Stě0000002134; Object Layer Attributes #2, Jednotka: m2; Object Layer Attributes #2, Název_objektu: Stěna; Object Layer Attributes #3, 2D interakce: yes; Object Layer Attributes #3, Status: Stávající; Object Layer Attributes #3, Práce: Zednické práce; Object Layer Attributes #3, Materiál: PÓROBETONOVÉ ZDIVO; Object Layer Attributes #3, Allright_Stavebni_dil_ID: 1352Stě0798434018; Object Layer Attributes #3, Jednotka: m2; Object Layer Attributes #3, Název_objektu: Stěna; Pset_WallCommon - LoadBearing: yes
ZELEZOBETONOVÁ KCE | Půdorys 1.PP | ZELEZOBETONOVÁ KCE 0.45 m, LIGNOPOR 0.025 m, PÓROBETONOVÉ ZDIVO 0.08 m |  | ZELEZOBETONOVÁ KCE | A | 1352HWa0000001856 | m3 | Celá stěna | Stávající | Betonářské práce | ZELEZOBETONOVÁ KCE |  | 1352Stě0000001857 | m3 | Stěna | 0 | 0.555 | 30.888 | 30.888 | 12.532 | 6.915 | 12.532 | 3.731 | 4.4 | NEMSOK - Object Layer Attributes #2, 2D interakce: yes; Object Layer Attributes #2, Status: Stávající; Object Layer Attributes #2, Práce: Zateplovací systémy; Object Layer Attributes #2, Materiál: LIGNOPOR; Object Layer Attributes #2, Allright_Stavebni_dil_ID: 1352Stě0000002022; Object Layer Attributes #2, Jednotka: m2; Object Layer Attributes #2, Název_objektu: Stěna; Object Layer Attributes #3, 2D interakce: yes; Object Layer Attributes #3, Status: Stávající; Object Layer Attributes #3, Práce: Zednické práce; Object Layer Attributes #3, Materiál: PÓROBETONOVÉ ZDIVO; Object Layer Attributes #3, Allright_Stavebni_dil_ID: 1352Stě0798433962; Object Layer Attributes #3, Jednotka: m2; Object Layer Attributes #3, Název_objektu: Stěna; Pset_WallCommon - LoadBearing: yes
ZELEZOBETONOVÁ KCE | Půdorys 1.PP | ZELEZOBETONOVÁ KCE 0.45 m, LIGNOPOR 0.025 m, PÓROBETONOVÉ ZDIVO 0.08 m |  | ZELEZOBETONOVÁ KCE | A | 1352HWa0000001845 | m3 | Celá stěna | Stávající | Betonářské práce | ZELEZOBETONOVÁ KCE |  | 1352Stě0000001846 | m3 | Stěna | 0 | 0.555 | 37.862 | 37.862 | 15.849 | 8.543 | 15.849 | 4.727 | 4.4 | NEMSOK - Object Layer Attributes #2, 2D interakce: yes; Object Layer Attributes #2, Status: Stávající; Object Layer Attributes #2, Práce: Zateplovací systémy; Object Layer Attributes #2, Materiál: LIGNOPOR; Object Layer Attributes #2, Allright_Stavebni_dil_ID: 1352Stě0000001943; Object Layer Attributes #2, Jednotka: m2; Object Layer Attributes #2, Název_objektu: Stěna; Object Layer Attributes #3, 2D interakce: yes; Object Layer Attributes #3, Status: Stávající; Object Layer Attributes #3, Práce: Zednické práce; Object Layer Attributes #3, Materiál: PÓROBETONOVÉ ZDIVO; Object Layer Attributes #3, Allright_Stavebni_dil_ID: 1352Stě0798433779; Object Layer Attributes #3, Jednotka: m2; Object Layer Attributes #3, Název_objektu: Stěna; Pset_WallCommon - LoadBearing: yes
ZELEZOBETONOVÁ KCE | Půdorys 1.PP | ZELEZOBETONOVÁ KCE 0.2 m | 1 | ZELEZOBETONOVÁ KCE | A | 1352HWa0000005071 | m3 | Celá stěna | Stávající | Betonářské práce | ZELEZOBETONOVÁ KCE | yes | 1352Stě0000005074 | m3 | Stěna | 0 | 0.2 | 3.89 | 3.65 | 0.778 | 1.06 | 0.73 | 0.212 | 3.67
ZELEZOBETONOVÁ KCE | Půdorys 1.PP | ZELEZOBETONOVÁ KCE 0.2 m | 1 | ZELEZOBETONOVÁ KCE | A | 1352HWa0000005215 | m3 | Celá stěna | Stávající | Betonářské práce | ZELEZOBETONOVÁ KCE | yes | 1352Stě0000005218 | m3 | Stěna | 0 | 0.2 | 3.89 | 3.89 | 0.778 | 1.06 | 0.778 | 0.212 | 3.67
ZELEZOBETONOVÁ KCE | Půdorys 1.PP | ZELEZOBETONOVÁ KCE 0.2 m | 1 | ZELEZOBETONOVÁ KCE | A | 1352HWa0000005045 | m3 | Celá stěna | Stávající | Betonářské práce | ZELEZOBETONOVÁ KCE | yes | 1352Stě0000005046 | m3 | Stěna | 0 | 0.2 | 3.89 | 3.65 | 0.778 | 1.06 | 0.73 | 0.212 | 3.67
ZELEZOBETONOVÁ KCE | Půdorys 1.PP | ZELEZOBETONOVÁ KCE 0.2 m | 1 | ZELEZOBETONOVÁ KCE | A | 1352HWa0000005101 | m3 | Celá stěna | Stávající | Betonářské práce | ZELEZOBETONOVÁ KCE | yes | 1352Stě0000005104 | m3 | Stěna | 0 | 0.2 | 3.89 | 3.65 | 0.778 | 1.06 | 0.73 | 0.212 | 3.67
ZELEZOBETONOVÁ KCE | Půdorys 1.PP | ZELEZOBETONOVÁ KCE 0.2 m | 1 | ZELEZOBETONOVÁ KCE | A | 1352HWa0000005318 | m3 | Celá stěna | Stávající | Betonářské práce | ZELEZOBETONOVÁ KCE | yes | 1352Stě0000005319 | m3 | Stěna | 0 | 0.2 | 4.763 | 4.763 | 0.953 | 1.26 | 0.953 | 0.252 | 3.78
ZELEZOBETONOVÁ KCE | Půdorys 1.PP | ZELEZOBETONOVÁ KCE 0.2 m | 1 | ZELEZOBETONOVÁ KCE | A | 1352HWa0000005360 | m3 | Celá stěna | Stávající | Betonářské práce | ZELEZOBETONOVÁ KCE | yes | 1352Stě0000005363 | m3 | Stěna | 0 | 0.2 | 4.007 | 3.767 | 0.801 | 1.06 | 0.753 | 0.212 | 3.78
ZELEZOBETONOVÁ KCE | Půdorys 1.PP | ZELEZOBETONOVÁ KCE 0.2 m | 1 | ZELEZOBETONOVÁ KCE | A | 1352HWa0000005371 | m3 | Celá stěna | Stávající | Betonářské práce | ZELEZOBETONOVÁ KCE | yes | 1352Stě0000005374 | m3 | Stěna | 0 | 0.2 | 4.007 | 3.767 | 0.801 | 1.06 | 0.753 | 0.212 | 3.78
ZELEZOBETONOVÁ KCE | Půdorys 1.PP | ZELEZOBETONOVÁ KCE 0.2 m | 1 | ZELEZOBETONOVÁ KCE | A | 1352HWa0000005386 | m3 | Celá stěna | Stávající | Betonářské práce | ZELEZOBETONOVÁ KCE | yes | 1352Stě0000005389 | m3 | Stěna | 0 | 0.2 | 4.007 | 4.007 | 0.801 | 1.06 | 0.801 | 0.212 | 3.78
ZELEZOBETONOVÁ KCE | Půdorys 1.PP | ZELEZOBETONOVÁ KCE 0.2 m | 1 | ZELEZOBETONOVÁ KCE | A | 1352HWa0000005451 | m3 | Celá stěna | Stávající | Betonářské práce | ZELEZOBETONOVÁ KCE | yes | 1352Stě0000005452 | m3 | Stěna | 0 | 0.2 | 4.007 | 3.767 | 0.801 | 1.06 | 0.753 | 0.212 | 3.78
ZELEZOBETONOVÁ KCE | Půdorys 1.PP | ZELEZOBETONOVÁ KCE 0.2 m | 1 | ZELEZOBETONOVÁ KCE | A | 1352HWa0000005469 | m3 | Celá stěna | Stávající | Betonářské práce | ZELEZOBETONOVÁ KCE | yes | 1352Stě0000005470 | m3 | Stěna | 0 | 0.2 | 4.763 | 4.763 | 0.953 | 1.26 | 0.953 | 0.252 | 3.78
ZELEZOBETONOVÁ KCE | Půdorys 1.PP | ZELEZOBETONOVÁ KCE 0.2 m | 1 | ZELEZOBETONOVÁ KCE | A | 1352HWa0000005487 | m3 | Celá stěna | Stávající | Betonářské práce | ZELEZOBETONOVÁ KCE | yes | 1352Stě0000005488 | m3 | Stěna | 0 | 0.2 | 4.007 | 3.767 | 0.801 | 1.06 | 0.753 | 0.212 | 3.78
ZDIVO Z CDm | Půdorys 1.PP | ZDIVO Z CDm 0.125 m | 1 | ZDIVO Z CDm | A | 1352HWa0798436707 | m3 | Celá stěna | Stávající | Zednické práce | ZDIVO Z CDm | yes | 1352Stě0798436708 | m3 | Stěna | 0 | 0.125 | 1.525 | 1.525 | 0.191 | 0.5 | 0.191 | 0.063 | 3.05
ZELEZOBETONOVÁ KCE | Půdorys 1.PP | ZELEZOBETONOVÁ KCE 0.25 m | 1 | ZELEZOBETONOVÁ KCE | A | 1352HWa0798436808 | m3 | Celá stěna | Stávající | Betonářské práce | ZELEZOBETONOVÁ KCE |  | 1352Stě0798436809 | m3 | Stěna | 0 | 0.25 | 2.596 | 2.596 | 0.649 | 0.775 | 0.649 | 0.194 | 3.35 | Pset_WallCommon - LoadBearing: yes
ZDIVO Z CDm | Půdorys 1.PP | ZDIVO Z CDm 0.125 m | 1 | ZDIVO Z CDm | A | 1352HWa0798437175 | m3 | Celá stěna | Stávající | Zednické práce | ZDIVO Z CDm | yes | 1352Stě0798437176 | m3 | Stěna | 0 | 0.125 | 8.311 | 8.311 | 1.039 | 2.725 | 1.039 | 0.341 | 3.05
PÓROBETONOVÉ ZDIVO | Půdorys 1.PP | PÓROBETONOVÉ ZDIVO 0.1 m | 1 | PÓROBETONOVÉ ZDIVO | EI 120 | 1352HWa0798437190 | m3 | Celá stěna | Stávající | Zednické práce | PÓROBETONOVÉ ZDIVO |  | 1352Stě0798437191 | m2 | Stěna | 1.111 | 0.1 | 1.525 | 1.525 | 0.153 | 0.5 | 0.153 | 0.05 | 3.05 | Pset_WallCommon - AcousticRating: 37 dB
PÓROBETONOVÉ ZDIVO | Půdorys 1.PP | PÓROBETONOVÉ ZDIVO 0.1 m | 1 | PÓROBETONOVÉ ZDIVO | EI 120 | 1352HWa0798437199 | m3 | Celá stěna | Stávající | Zednické práce | PÓROBETONOVÉ ZDIVO |  | 1352Stě0798437200 | m2 | Stěna | 1.111 | 0.1 | 5.566 | 5.566 | 0.557 | 1.825 | 0.557 | 0.183 | 3.05 | Pset_WallCommon - AcousticRating: 37 dB
ZDIVO Z CDm | Půdorys 1.PP | ZDIVO Z CDm 0.125 m | 1 | ZDIVO Z CDm | A | 1352HWa0798437747 | m3 | Celá stěna | Stávající | Zednické práce | ZDIVO Z CDm | yes | 1352Stě0798437751 | m3 | Stěna | 0 | 0.125 | 7.625 | 5.807 | 0.953 | 2.5 | 0.726 | 0.312 | 3.05
ZDIVO Z CDm | Půdorys 1.PP | ZDIVO Z CDm 0.125 m |  | ZDIVO Z CDm | A | 1352HWa0798437615 | m3 | Celá stěna | Stávající | Zednické práce | ZDIVO Z CDm | yes | 1352Stě0798437616 | m3 | Stěna | 0 | 0.125 | 3.511 | 3.511 | 0.439 | 2.09 | 0.439 | 0.261 | 1.68
PÓROBETONOVÉ ZDIVO | Půdorys 1.PP | PÓROBETONOVÉ ZDIVO 0.1 m | 1 | PÓROBETONOVÉ ZDIVO | EI 120 | 1352HWa0798438156 | m3 | Celá stěna | Stávající | Zednické práce | PÓROBETONOVÉ ZDIVO |  | 1352Stě0798438157 | m2 | Stěna | 1.111 | 0.1 | 6.558 | 6.558 | 0.656 | 2.15 | 0.656 | 0.215 | 3.05 | Pset_WallCommon - AcousticRating: 37 dB
ZDIVO Z CDm | Půdorys 1.PP | ZDIVO Z CDm 0.125 m | 1 | ZDIVO Z CDm | A | 1352HWa0798439022 | m3 | Celá stěna | Stávající | Zednické práce | ZDIVO Z CDm | yes | 1352Stě0798439023 | m3 | Stěna | 0 | 0.125 | 17.08 | 13.912 | 2.135 | 5.6 | 1.739 | 0.7 | 3.05
ZELEZOBETONOVÁ KCE | Půdorys 1.PP | ZELEZOBETONOVÁ KCE 0.2 m, LIGNOPOR 0.025 m, PÓROBETONOVÉ ZDIVO 0.08 m |  | ZELEZOBETONOVÁ KCE | A | 1352HWa0798431255 | m3 | Celá stěna | Stávající | Betonářské práce | ZELEZOBETONOVÁ KCE |  | 1352Stě0798431261 | m3 | Stěna | 0 | 0.305 | 7.973 | 6.173 | 1.971 | 2.205 | 1.566 | 0.698 | 3.35 | NEMSOK - Object Layer Attributes #2, 2D interakce: yes; Object Layer Attributes #2, Status: Stávající; Object Layer Attributes #2, Práce: Zateplovací systémy; Object Layer Attributes #2, Materiál: LIGNOPOR; Object Layer Attributes #2, Allright_Stavebni_dil_ID: 1352Stě0798431262; Object Layer Attributes #2, Jednotka: m2; Object Layer Attributes #2, Název_objektu: Stěna; Object Layer Attributes #3, 2D interakce: yes; Object Layer Attributes #3, Status: Stávající; Object Layer Attributes #3, Práce: Zednické práce; Object Layer Attributes #3, Materiál: PÓROBETONOVÉ ZDIVO; Object Layer Attributes #3, Allright_Stavebni_dil_ID: 1352Stě0798431306; Object Layer Attributes #3, Jednotka: m2; Object Layer Attributes #3, Název_objektu: Stěna; Pset_WallCommon - LoadBearing: yes
ZELEZOBETONOVÁ KCE | Půdorys 1.PP | ZELEZOBETONOVÁ KCE 0.2 m, LIGNOPOR 0.025 m, PÓROBETONOVÉ ZDIVO 0.08 m |  | ZELEZOBETONOVÁ KCE | A | 1352HWa0798431695 | m3 | Celá stěna | Stávající | Betonářské práce | ZELEZOBETONOVÁ KCE |  | 1352Stě0798431708 | m3 | Stěna | 0 | 0.305 | 34.505 | 27.755 | 8.673 | 10.092 | 7.097 | 3.102 | 3.35 | NEMSOK - Object Layer Attributes #2, 2D interakce: yes; Object Layer Attributes #2, Status: Stávající; Object Layer Attributes #2, Práce: Zateplovací systémy; Object Layer Attributes #2, Materiál: LIGNOPOR; Object Layer Attributes #2, Allright_Stavebni_dil_ID: 1352Stě0798431707; Object Layer Attributes #2, Jednotka: m2; Object Layer Attributes #2, Název_objektu: Stěna; Object Layer Attributes #3, 2D interakce: yes; Object Layer Attributes #3, Status: Stávající; Object Layer Attributes #3, Práce: Zednické práce; Object Layer Attributes #3, Materiál: PÓROBETONOVÉ ZDIVO; Object Layer Attributes #3, Allright_Stavebni_dil_ID: 1352Stě0798431848; Object Layer Attributes #3, Jednotka: m2; Object Layer Attributes #3, Název_objektu: Stěna; Pset_WallCommon - LoadBearing: yes
ZELEZOBETONOVÁ KCE | Půdorys 1.PP | ZELEZOBETONOVÁ KCE 0.2 m, LIGNOPOR 0.025 m, PÓROBETONOVÉ ZDIVO 0.08 m |  | ZELEZOBETONOVÁ KCE | A | 1352HWa0798433035 | m3 | Celá stěna | Stávající | Betonářské práce | ZELEZOBETONOVÁ KCE |  | 1352Stě0798433060 | m3 | Stěna | 0 | 0.305 | 43.048 | 34.048 | 10.855 | 12.708 | 8.752 | 3.896 | 3.35 | NEMSOK - Object Layer Attributes #2, 2D interakce: yes; Object Layer Attributes #2, Status: Stávající; Object Layer Attributes #2, Práce: Zateplovací systémy; Object Layer Attributes #2, Materiál: LIGNOPOR; Object Layer Attributes #2, Allright_Stavebni_dil_ID: 1352Stě0798433059; Object Layer Attributes #2, Jednotka: m2; Object Layer Attributes #2, Název_objektu: Stěna; Object Layer Attributes #3, 2D interakce: yes; Object Layer Attributes #3, Status: Stávající; Object Layer Attributes #3, Práce: Zednické práce; Object Layer Attributes #3, Materiál: PÓROBETONOVÉ ZDIVO; Object Layer Attributes #3, Allright_Stavebni_dil_ID: 1352Stě0798433142; Object Layer Attributes #3, Jednotka: m2; Object Layer Attributes #3, Název_objektu: Stěna; Pset_WallCommon - LoadBearing: yes
PÓROBETONOVÉ ZDIVO | Půdorys 1.PP | PÓROBETONOVÉ ZDIVO 0.1 m | 1 | PÓROBETONOVÉ ZDIVO | EI 120 | 1352HWa0798441407 | m3 | Celá stěna | Stávající | Zednické práce | PÓROBETONOVÉ ZDIVO |  | 1352Stě0798441408 | m2 | Stěna | 1.111 | 0.1 | 17.08 | 14.83 | 1.708 | 5.6 | 1.483 | 0.56 | 3.05 | Pset_WallCommon - AcousticRating: 37 dB
PÓROBETONOVÉ ZDIVO | Půdorys 1.PP | PÓROBETONOVÉ ZDIVO 0.1 m | 1 | PÓROBETONOVÉ ZDIVO | EI 120 | 1352HWa0798441414 | m3 | Celá stěna | Stávající | Zednické práce | PÓROBETONOVÉ ZDIVO |  | 1352Stě0798441415 | m2 | Stěna | 1.111 | 0.1 | 1.678 | 1.678 | 0.168 | 0.55 | 0.168 | 0.055 | 3.05 | Pset_WallCommon - AcousticRating: 37 dB
ZDIVO Z CDm | Půdorys 1.PP | ZDIVO Z CDm 0.125 m | 1 | ZDIVO Z CDm | A | 1352HWa0798441908 | m3 | Celá stěna | Stávající | Zednické práce | ZDIVO Z CDm | yes | 1352Stě0798441909 | m3 | Stěna | 0 | 0.125 | 1.678 | 1.678 | 0.21 | 0.55 | 0.21 | 0.069 | 3.05
ZELEZOBETONOVÁ KCE | Půdorys 1.PP | ZELEZOBETONOVÁ KCE 0.45 m, LIGNOPOR 0.025 m, PÓROBETONOVÉ ZDIVO 0.08 m |  | ZELEZOBETONOVÁ KCE | A | 1352HWa0000001901 | m3 | Celá stěna | Stávající | Betonářské práce | ZELEZOBETONOVÁ KCE |  | 1352Stě0000001902 | m3 | Stěna | 0 | 0.555 | 38.262 | 38.262 | 16.043 | 8.645 | 16.043 | 4.785 | 4.4 | NEMSOK - Object Layer Attributes #2, 2D interakce: yes; Object Layer Attributes #2, Status: Stávající; Object Layer Attributes #2, Práce: Zateplovací systémy; Object Layer Attributes #2, Materiál: LIGNOPOR; Object Layer Attributes #2, Allright_Stavebni_dil_ID: 1352Stě0000002062; Object Layer Attributes #2, Jednotka: m2; Object Layer Attributes #2, Název_objektu: Stěna; Object Layer Attributes #3, 2D interakce: yes; Object Layer Attributes #3, Status: Stávající; Object Layer Attributes #3, Práce: Zednické práce; Object Layer Attributes #3, Materiál: PÓROBETONOVÉ ZDIVO; Object Layer Attributes #3, Allright_Stavebni_dil_ID: 1352Stě0798433843; Object Layer Attributes #3, Jednotka: m2; Object Layer Attributes #3, Název_objektu: Stěna; Pset_WallCommon - LoadBearing: yes
ZELEZOBETONOVÁ KCE | Půdorys 1.PP | ZELEZOBETONOVÁ KCE 0.25 m, LIGNOPOR 0.025 m, PÓROBETONOVÉ ZDIVO 0.08 m | 1 | ZELEZOBETONOVÁ KCE | A | 1352HWa0000003979 | m3 | Celá stěna | Stávající | Betonářské práce | ZELEZOBETONOVÁ KCE |  | 1352Stě0000003980 | m3 | Stěna | 0 | 0.355 | 15.324 | 15.256 | 4.538 | 3.676 | 4.532 | 1.299 | 4.1 | NEMSOK - Object Layer Attributes #2, 2D interakce: yes; Object Layer Attributes #2, Status: Stávající; Object Layer Attributes #2, Práce: Zateplovací systémy; Object Layer Attributes #2, Materiál: LIGNOPOR; Object Layer Attributes #2, Allright_Stavebni_dil_ID: 1352Stě0000003981; Object Layer Attributes #2, Jednotka: m2; Object Layer Attributes #2, Název_objektu: Stěna; Object Layer Attributes #3, 2D interakce: yes; Object Layer Attributes #3, Status: Stávající; Object Layer Attributes #3, Práce: Zednické práce; Object Layer Attributes #3, Materiál: PÓROBETONOVÉ ZDIVO; Object Layer Attributes #3, Allright_Stavebni_dil_ID: 1352Stě0798434167; Object Layer Attributes #3, Jednotka: m2; Object Layer Attributes #3, Název_objektu: Stěna; Pset_WallCommon - LoadBearing: yes
ZELEZOBETONOVÁ KCE | Půdorys 1.PP | PÓROBETONOVÉ ZDIVO 0.08 m | 1 | ZELEZOBETONOVÁ KCE | A | 1352HWa0798442532 | m3 | Celá stěna | Stávající | Zednické práce | PÓROBETONOVÉ ZDIVO | no | 1352Stě0798442533 | m2 | Stěna | 0 | 0.08 | 4.474 | 4.474 | 0.358 | 1.017 | 0.358 | 0.081 | 4.4 | Pset_WallCommon - LoadBearing: yes
ZELEZOBETONOVÁ KCE | Půdorys 1.PP | ZELEZOBETONOVÁ KCE 0.25 m, LIGNOPOR 0.025 m | 1 | ZELEZOBETONOVÁ KCE | A | 1352HWa0798442354 | m3 | Celá stěna | Stávající | Betonářské práce | ZELEZOBETONOVÁ KCE |  | 1352Stě0798442356 | m3 | Stěna | 0 | 0.275 | 2.571 | 2.571 | 0.699 | 0.767 | 0.699 | 0.211 | 3.35 | NEMSOK - Object Layer Attributes #2, 2D interakce: yes; Object Layer Attributes #2, Status: Stávající; Object Layer Attributes #2, Práce: Zateplovací systémy; Object Layer Attributes #2, Materiál: LIGNOPOR; Object Layer Attributes #2, Allright_Stavebni_dil_ID: 1352Stě0798442357; Object Layer Attributes #2, Jednotka: m2; Object Layer Attributes #2, Název_objektu: Stěna; Pset_WallCommon - LoadBearing: yes
ZELEZOBETONOVÁ KCE | Půdorys 1.PP | ZELEZOBETONOVÁ KCE 0.45 m, LIGNOPOR 0.025 m | 1 | ZELEZOBETONOVÁ KCE | A | 1352HWa0798442317 | m3 | Celá stěna | Stávající | Betonářské práce | ZELEZOBETONOVÁ KCE |  | 1352Stě0798442321 | m3 | Stěna | 0 | 0.475 | 2.133 | 2.133 | 0.329 | 0.442 | 0.329 | 0.104 | 3.18 | NEMSOK - Object Layer Attributes #2, 2D interakce: yes; Object Layer Attributes #2, Status: Stávající; Object Layer Attributes #2, Práce: Zateplovací systémy; Object Layer Attributes #2, Materiál: LIGNOPOR; Object Layer Attributes #2, Allright_Stavebni_dil_ID: 1352Stě0798442320; Object Layer Attributes #2, Jednotka: m2; Object Layer Attributes #2, Název_objektu: Stěna; Pset_WallCommon - LoadBearing: yes
ZDIVO Z CDm | Půdorys 1.PP | ZDIVO Z CDm 0.125 m | 1 | ZDIVO Z CDm | A | 1352HWa0798442929 | m3 | Celá stěna | Stávající | Zednické práce | ZDIVO Z CDm | yes | 1352Stě0798442930 | m3 | Stěna | 0 | 0.125 | 3.279 | 3.279 | 0.41 | 1.075 | 0.41 | 0.134 | 3.05
ZDIVO Z CDm | Půdorys 1.PP | ZDIVO Z CDm 0.125 m | 1 | ZDIVO Z CDm | A | 1352HWa0798442949 | m3 | Celá stěna | Stávající | Zednické práce | ZDIVO Z CDm | yes | 1352Stě0798442950 | m3 | Stěna | 0 | 0.125 | 1.525 | 1.525 | 0.191 | 0.5 | 0.191 | 0.063 | 3.05
ZDIVO Z CDm | Půdorys 1.PP | ZDIVO Z CDm 0.125 m | 1 | ZDIVO Z CDm | A | 1352HWa0798442967 | m3 | Celá stěna | Stávající | Zednické práce | ZDIVO Z CDm | yes | 1352Stě0798442968 | m3 | Stěna | 0 | 0.125 | 0.839 | 0.839 | 0.105 | 0.275 | 0.105 | 0.034 | 3.05
ZDIVO Z CDm | Půdorys 1.PP | ZDIVO Z CDm 0.125 m | 1 | ZDIVO Z CDm | A | 1352HWa0798442988 | m3 | Celá stěna | Stávající | Zednické práce | ZDIVO Z CDm | yes | 1352Stě0798442989 | m3 | Stěna | 0 | 0.125 | 1.144 | 1.144 | 0.143 | 0.375 | 0.143 | 0.047 | 3.05
PÓROBETONOVÉ ZDIVO | Půdorys 1.PP | PÓROBETONOVÉ ZDIVO 0.1 m | 1 | PÓROBETONOVÉ ZDIVO | EI 120 | 1352HWa0798443155 | m3 | Celá stěna | Stávající | Zednické práce | PÓROBETONOVÉ ZDIVO |  | 1352Stě0798443156 | m2 | Stěna | 1.111 | 0.1 | 16.47 | 16.47 | 1.647 | 5.4 | 1.647 | 0.54 | 3.05 | Pset_WallCommon - AcousticRating: 37 dB
ZDIVO Z CDm | Půdorys 1.PP | ZDIVO Z CDm 0.125 m | 1 | ZDIVO Z CDm | A | 1352HWa0798443190 | m3 | Celá stěna | Stávající | Zednické práce | ZDIVO Z CDm | yes | 1352Stě0798443191 | m3 | Stěna | 0 | 0.125 | 1.22 | 1.22 | 0.152 | 0.4 | 0.152 | 0.05 | 3.05
ZDIVO Z CDm | Půdorys 1.PP | ZDIVO Z CDm 0.125 m | 1 | ZDIVO Z CDm | A | 1352HWa0798443199 | m3 | Celá stěna | Stávající | Zednické práce | ZDIVO Z CDm | yes | 1352Stě0798443200 | m3 | Stěna | 0 | 0.125 | 2.364 | 2.364 | 0.295 | 0.775 | 0.295 | 0.097 | 3.05
ZDIVO Z CDm | Půdorys 1.PP | ZDIVO Z CDm 0.125 m | 1 | ZDIVO Z CDm | A | 1352HWa0798443181 | m3 | Celá stěna | Stávající | Zednické práce | ZDIVO Z CDm | yes | 1352Stě0798443182 | m3 | Stěna | 0 | 0.125 | 10.599 | 10.599 | 1.325 | 3.475 | 1.325 | 0.434 | 3.05
ZDIVO Z CDm | Půdorys 1.PP | ZDIVO Z CDm 0.125 m | 1 | ZDIVO Z CDm | A | 1352HWa0798443327 | m3 | Celá stěna | Stávající | Zednické práce | ZDIVO Z CDm | yes | 1352Stě0798443328 | m3 | Stěna | 0 | 0.125 | 0.915 | 0.915 | 0.114 | 0.3 | 0.114 | 0.037 | 3.05
ZDIVO Z CDm | Půdorys 1.PP | ZDIVO Z CDm 0.125 m | 1 | ZDIVO Z CDm | A | 1352HWa0798443337 | m3 | Celá stěna | Stávající | Zednické práce | ZDIVO Z CDm | yes | 1352Stě0798443338 | m3 | Stěna | 0 | 0.125 | 3.126 | 3.126 | 0.391 | 1.025 | 0.391 | 0.128 | 3.05
ZDIVO Z CDm | Půdorys 1.PP | ZDIVO Z CDm 0.125 m | 1 | ZDIVO Z CDm | A | 1352HWa0798443443 | m3 | Celá stěna | Stávající | Zednické práce | ZDIVO Z CDm | yes | 1352Stě0798443444 | m3 | Stěna | 0 | 0.125 | 2.745 | 1.962 | 0.343 | 0.9 | 0.245 | 0.112 | 3.05
ZDIVO Z CDm | Půdorys 1.PP | ZDIVO Z CDm 0.125 m | 1 | ZDIVO Z CDm | A | 1352HWa0798442934 | m3 | Celá stěna | Stávající | Zednické práce | ZDIVO Z CDm | yes | 1352Stě0798442935 | m3 | Stěna | 0 | 0.125 | 1.22 | 1.22 | 0.153 | 0.4 | 0.153 | 0.05 | 3.05
ZDIVO Z CDm | Půdorys 1.PP | ZDIVO Z CDm 0.125 m | 1 | ZDIVO Z CDm | A | 1352HWa0798437033 | m3 | Celá stěna | Stávající | Zednické práce | ZDIVO Z CDm | yes | 1352Stě0798437034 | m3 | Stěna | 0 | 0.125 | 2.516 | 2.516 | 0.315 | 0.825 | 0.315 | 0.103 | 3.05
ZDIVO Z CDm | Půdorys 1.PP | ZDIVO Z CDm 0.125 m | 1 | ZDIVO Z CDm | A | 1352HWa0798437043 | m3 | Celá stěna | Stávající | Zednické práce | ZDIVO Z CDm | yes | 1352Stě0798437044 | m3 | Stěna | 0 | 0.125 | 1.144 | 1.144 | 0.143 | 0.375 | 0.143 | 0.047 | 3.05
ZDIVO Z CDm | Půdorys 1.PP | ZDIVO Z CDm 0.125 m | 1 | ZDIVO Z CDm | A | 1352HWa0798443350 | m3 | Celá stěna | Stávající | Zednické práce | ZDIVO Z CDm | yes | 1352Stě0798443351 | m3 | Stěna | 0 | 0.125 | 0.534 | 0.534 | 0.067 | 0.175 | 0.067 | 0.022 | 3.05
ZDIVO Z CDm | Půdorys 1.PP | ZDIVO Z CDm 0.125 m | 1 | ZDIVO Z CDm | A | 1352HWa0798449628 | m3 | Celá stěna | Stávající | Zednické práce | ZDIVO Z CDm | yes | 1352Stě0798449630 | m3 | Stěna | 0 | 0.125 | 0.793 | 0.793 | 0.099 | 0.26 | 0.099 | 0.032 | 3.05
ZDIVO Z CDm | Půdorys 1.PP | ZDIVO Z CDm 0.125 m |  | ZDIVO Z CDm | A | 1352HWa0798449613 | m3 | Celá stěna | Stávající | Zednické práce | ZDIVO Z CDm | yes | 1352Stě0798449615 | m3 | Stěna | 0 | 0.125 | 0.909 | 0.909 | 0.114 | 0.3 | 0.114 | 0.038 | 3.03
ZDIVO Z CDm | Půdorys 1.PP | ZDIVO Z CDm 0.125 m |  | ZDIVO Z CDm | A | 1352HWa0798449598 | m3 | Celá stěna | Stávající | Zednické práce | ZDIVO Z CDm | yes | 1352Stě0798449600 | m3 | Stěna | 0 | 0.125 | 0.864 | 0.864 | 0.108 | 0.3 | 0.108 | 0.038 | 2.88
ZDIVO Z CDm | Půdorys 1.PP | ZDIVO Z CDm 0.125 m |  | ZDIVO Z CDm | A | 1352HWa0798449583 | m3 | Celá stěna | Stávající | Zednické práce | ZDIVO Z CDm | yes | 1352Stě0798449585 | m3 | Stěna | 0 | 0.125 | 0.819 | 0.819 | 0.102 | 0.3 | 0.102 | 0.038 | 2.73
ZDIVO Z CDm | Půdorys 1.PP | ZDIVO Z CDm 0.125 m |  | ZDIVO Z CDm | A | 1352HWa0798449568 | m3 | Celá stěna | Stávající | Zednické práce | ZDIVO Z CDm | yes | 1352Stě0798449570 | m3 | Stěna | 0 | 0.125 | 0.774 | 0.774 | 0.097 | 0.3 | 0.097 | 0.037 | 2.58
ZDIVO Z CDm | Půdorys 1.PP | ZDIVO Z CDm 0.125 m |  | ZDIVO Z CDm | A | 1352HWa0798449553 | m3 | Celá stěna | Stávající | Zednické práce | ZDIVO Z CDm | yes | 1352Stě0798449555 | m3 | Stěna | 0 | 0.125 | 0.729 | 0.729 | 0.091 | 0.3 | 0.091 | 0.038 | 2.43
ZDIVO Z CDm | Půdorys 1.PP | ZDIVO Z CDm 0.125 m |  | ZDIVO Z CDm | A | 1352HWa0798449538 | m3 | Celá stěna | Stávající | Zednické práce | ZDIVO Z CDm | yes | 1352Stě0798449540 | m3 | Stěna | 0 | 0.125 | 0.684 | 0.684 | 0.086 | 0.3 | 0.086 | 0.038 | 2.28
ZDIVO Z CDm | Půdorys 1.PP | ZDIVO Z CDm 0.125 m |  | ZDIVO Z CDm | A | 1352HWa0798449523 | m3 | Celá stěna | Stávající | Zednické práce | ZDIVO Z CDm | yes | 1352Stě0798449525 | m3 | Stěna | 0 | 0.125 | 0.639 | 0.639 | 0.08 | 0.3 | 0.08 | 0.038 | 2.13
ZDIVO Z CDm | Půdorys 1.PP | ZDIVO Z CDm 0.125 m |  | ZDIVO Z CDm | A | 1352HWa0798449508 | m3 | Celá stěna | Stávající | Zednické práce | ZDIVO Z CDm | yes | 1352Stě0798449510 | m3 | Stěna | 0 | 0.125 | 0.594 | 0.594 | 0.074 | 0.3 | 0.074 | 0.038 | 1.98
ZDIVO Z CDm | Půdorys 1.PP | ZDIVO Z CDm 0.125 m |  | ZDIVO Z CDm | A | 1352HWa0798437782 | m3 | Celá stěna | Stávající | Zednické práce | ZDIVO Z CDm | yes | 1352Stě0798437784 | m3 | Stěna | 0 | 0.125 | 0.549 | 0.549 | 0.069 | 0.3 | 0.069 | 0.038 | 1.83
ZDIVO Z CDm | Půdorys 1.PP | ZDIVO Z CDm 0.125 m | 1 | ZDIVO Z CDm | A | 1352HWa0798436780 | m3 | Celá stěna | Stávající | Zednické práce | ZDIVO Z CDm | yes | 1352Stě0798436781 | m3 | Stěna | 0 | 0.125 | 7.32 | 4.034 | 0.915 | 2.4 | 0.504 | 0.3 | 3.05
ZDIVO Z CDm | Půdorys 1.PP | ZDIVO Z CDm 0.3 m | 1 | ZDIVO Z CDm | REI 120 | 1352HWa0798436773 | m3 | Celá stěna | Stávající | Zednické práce | ZDIVO Z CDm |  | 1352Stě0798436774 | m3 | Stěna | 0.22 | 0.3 | 1.601 | 1.601 | 0.48 | 0.525 | 0.48 | 0.157 | 3.05 | Pset_WallCommon - AcousticRating: 47 dB
ZDIVO Z CDm | Půdorys 1.PP | ZDIVO Z CDm 0.125 m | 1 | ZDIVO Z CDm | A | 1352HWa0798450351 | m3 | Celá stěna | Stávající | Zednické práce | ZDIVO Z CDm | yes | 1352Stě0798450352 | m3 | Stěna | 0 | 0.125 | 1.906 | 1.906 | 0.238 | 0.625 | 0.238 | 0.078 | 3.05
ZDIVO Z CDm | Půdorys 1.PP | ZDIVO Z CDm 0.125 m | 1 | ZDIVO Z CDm | A | 1352HWa0798450356 | m3 | Celá stěna | Stávající | Zednické práce | ZDIVO Z CDm | yes | 1352Stě0798450357 | m3 | Stěna | 0 | 0.125 | 6.1 | 3.855 | 0.762 | 2 | 0.482 | 0.25 | 3.05
ZDIVO Z CDm | Půdorys 1.PP | ZDIVO Z CDm 0.125 m | 1 | ZDIVO Z CDm | A | 1352HWa0798450384 | m3 | Celá stěna | Stávající | Zednické práce | ZDIVO Z CDm | yes | 1352Stě0798450385 | m3 | Stěna | 0 | 0.125 | 1.601 | 1.601 | 0.2 | 0.525 | 0.2 | 0.066 | 3.05
ZDIVO Z CDm | Půdorys 1.PP | ZDIVO Z CDm 0.125 m | 1 | ZDIVO Z CDm | A | 1352HWa0798450565 | m3 | Celá stěna | Stávající | Zednické práce | ZDIVO Z CDm | yes | 1352Stě0798450566 | m3 | Stěna | 0 | 0.125 | 1.982 | 1.983 | 0.248 | 0.65 | 0.248 | 0.081 | 3.05
PÓROBETONOVÉ ZDIVO | Půdorys 1.PP | PÓROBETONOVÉ ZDIVO 0.1 m | 1 | PÓROBETONOVÉ ZDIVO | EI 120 | 1352HWa0798442998 | m3 | Celá stěna | Stávající | Zednické práce | PÓROBETONOVÉ ZDIVO |  | 1352Stě0798442999 | m2 | Stěna | 1.111 | 0.1 | 8.54 | 6.29 | 0.854 | 2.8 | 0.629 | 0.28 | 3.05 | Pset_WallCommon - AcousticRating: 37 dB
PÓROBETONOVÉ ZDIVO | Půdorys 1.PP | PÓROBETONOVÉ ZDIVO 0.1 m | 1 | PÓROBETONOVÉ ZDIVO | EI 120 | 1352HWa0798450926 | m3 | Celá stěna | Stávající | Zednické práce | PÓROBETONOVÉ ZDIVO |  | 1352Stě0798450932 | m2 | Stěna | 1.111 | 0.1 | 8.159 | 5.909 | 0.816 | 2.675 | 0.591 | 0.268 | 3.05 | Pset_WallCommon - AcousticRating: 37 dB
ZELEZOBETONOVÁ KCE | Půdorys 1.PP | ZELEZOBETONOVÁ KCE 0.15 m | 1 | ZELEZOBETONOVÁ KCE | A | 1352HWa0798451894 | m3 | Celá stěna | Stávající | Betonářské práce | ZELEZOBETONOVÁ KCE |  | 1352Stě0798451895 | m3 | Stěna | 0 | 0.15 | 1.715 | 1.716 | 0.257 | 2.35 | 0.257 | 0.352 | 0.73
ZELEZOBETONOVÁ KCE | Půdorys 1.PP | ZELEZOBETONOVÁ KCE 0.15 m | 1 | ZELEZOBETONOVÁ KCE | A | 1352HWa0798451899 | m3 | Celá stěna | Stávající | Betonářské práce | ZELEZOBETONOVÁ KCE |  | 1352Stě0798451900 | m3 | Stěna | 0 | 0.15 | 0.511 | 0.511 | 0.077 | 0.7 | 0.077 | 0.105 | 0.73
ZELEZOBETONOVÁ KCE | Půdorys 1.PP | ZELEZOBETONOVÁ KCE 0.15 m | 1 | ZELEZOBETONOVÁ KCE | A | 1352HWa0798451909 | m3 | Celá stěna | Stávající | Betonářské práce | ZELEZOBETONOVÁ KCE |  | 1352Stě0798451910 | m3 | Stěna | 0 | 0.15 | 2.153 | 2.154 | 0.323 | 2.95 | 0.323 | 0.442 | 0.73
ZELEZOBETONOVÁ KCE | Půdorys 1.PP | ZELEZOBETONOVÁ KCE 0.15 m | 1 | ZELEZOBETONOVÁ KCE | A | 1352HWa0798451921 | m3 | Celá stěna | Stávající | Betonářské práce | ZELEZOBETONOVÁ KCE |  | 1352Stě0798451922 | m3 | Stěna | 0 | 0.15 | 2.665 | 2.665 | 0.4 | 3.65 | 0.4 | 0.548 | 0.73
ZELEZOBETONOVÁ KCE | Půdorys 1.PP | ZELEZOBETONOVÁ KCE 0.15 m | 1 | ZELEZOBETONOVÁ KCE | A | 1352HWa0798451941 | m3 | Celá stěna | Stávající | Betonářské práce | ZELEZOBETONOVÁ KCE |  | 1352Stě0798451942 | m3 | Stěna | 0 | 0.15 | 1.606 | 1.606 | 0.241 | 2.2 | 0.241 | 0.33 | 0.73
ZELEZOBETONOVÁ KCE | Půdorys 1.PP | ZELEZOBETONOVÁ KCE 0.15 m | 1 | ZELEZOBETONOVÁ KCE | A | 1352HWa0798451990 | m3 | Celá stěna | Stávající | Betonářské práce | ZELEZOBETONOVÁ KCE |  | 1352Stě0798451991 | m3 | Stěna | 0 | 0.15 | 7.172 | 7.172 | 1.076 | 9.825 | 1.076 | 1.474 | 0.73
ZELEZOBETONOVÁ KCE | Půdorys 1.PP | ZELEZOBETONOVÁ KCE 0.15 m | 1 | ZELEZOBETONOVÁ KCE | A | 1352HWa0798452237 | m3 | Celá stěna | Stávající | Betonářské práce | ZELEZOBETONOVÁ KCE |  | 1352Stě0798452238 | m3 | Stěna | 0 | 0.15 | 8.377 | 8.377 | 1.257 | 11.475 | 1.257 | 1.721 | 0.73
ZELEZOBETONOVÁ KCE | Půdorys 1.PP | ZELEZOBETONOVÁ KCE 0.15 m | 1 | ZELEZOBETONOVÁ KCE | A | 1352HWa0798452263 | m3 | Celá stěna | Stávající | Betonářské práce | ZELEZOBETONOVÁ KCE |  | 1352Stě0798452264 | m3 | Stěna | 0 | 0.15 | 1.132 | 1.132 | 0.17 | 1.55 | 0.17 | 0.232 | 0.73
ZELEZOBETONOVÁ KCE | Půdorys 1.PP | ZELEZOBETONOVÁ KCE 0.15 m | 1 | ZELEZOBETONOVÁ KCE | A | 1352HWa0798452283 | m3 | Celá stěna | Stávající | Betonářské práce | ZELEZOBETONOVÁ KCE |  | 1352Stě0798452284 | m3 | Stěna | 0 | 0.15 | 0.694 | 0.694 | 0.104 | 0.95 | 0.104 | 0.143 | 0.73
PÓROBETONOVÉ ZDIVO | Půdorys 1.PP | PÓROBETONOVÉ ZDIVO 0.1 m | 1 | PÓROBETONOVÉ ZDIVO | EI 120 | 1352HWa0798452883 | m3 | Celá stěna | Stávající | Zednické práce | PÓROBETONOVÉ ZDIVO |  | 1352Stě0798452886 | m2 | Stěna | 1.111 | 0.1 | 7.244 | 4.094 | 0.724 | 2.375 | 0.409 | 0.237 | 3.05 | Pset_WallCommon - AcousticRating: 37 dB
ZELEZOBETONOVÁ KCE | Půdorys 1.PP | ZELEZOBETONOVÁ KCE 0.742462 m |  | ZELEZOBETONOVÁ KCE | A | 1352HWa0798442673 | m3 | Celá stěna | Stávající | Betonářské práce | ZELEZOBETONOVÁ KCE | no | 1352Stě0798442674 | m3 | Stěna | 0 | 0.371 | 2.361 | 1.181 | 0.876 | 0.742 | 0.876 | 0.276 | 3.18 | Pset_WallCommon - LoadBearing: yes
ZDIVO Z CDm | Půdorys 1.PP | ZDIVO Z CDm 0.125 m | 1 | ZDIVO Z CDm | A | 1352HWa0000012874 | m3 | Celá stěna | Stávající | Zednické práce | ZDIVO Z CDm | yes | 1352Stě0000012875 | m3 | Stěna | 0 | 0.125 | 1.144 | 1.144 | 0.143 | 0.375 | 0.143 | 0.047 | 3.05
ZDIVO Z CDm | Půdorys 1.PP | ZDIVO Z CDm 0.125 m | 1 | ZDIVO Z CDm | A | 1352HWa0000013131 | m3 | Celá stěna | Stávající | Zednické práce | ZDIVO Z CDm | yes | 1352Stě0000013136 | m3 | Stěna | 0 | 0.125 | 0.305 | 0.305 | 0.038 | 0.1 | 0.038 | 0.013 | 3.05
ZDIVO Z CDm | Půdorys 1.PP | ZDIVO Z CDm 0.125 m | 1 | ZDIVO Z CDm | A | 1352HWa0000013155 | m3 | Celá stěna | Stávající | Zednické práce | ZDIVO Z CDm | yes | 1352Stě0000013156 | m3 | Stěna | 0 | 0.125 | 2.745 | 2.745 | 0.343 | 0.9 | 0.343 | 0.113 | 3.05
ZDIVO Z CDm | Půdorys 1.PP | ZDIVO Z CDm 0.125 m | 1 | ZDIVO Z CDm | A | 1352HWa0000013237 | m3 | Celá stěna | Stávající | Zednické práce | ZDIVO Z CDm | yes | 1352Stě0000013238 | m3 | Stěna | 0 | 0.125 | 14.03 | 14.03 | 1.754 | 4.6 | 1.754 | 0.575 | 3.05
ZDIVO Z CDm | Půdorys 1.PP | ZDIVO Z CDm 0.125 m | 1 | ZDIVO Z CDm | A | 1352HWa0000013242 | m3 | Celá stěna | Stávající | Zednické práce | ZDIVO Z CDm | yes | 1352Stě0000013243 | m3 | Stěna | 0 | 0.125 | 10.98 | 7.849 | 1.372 | 3.6 | 0.981 | 0.45 | 3.05
ZDIVO Z CDm | Půdorys 1.PP | ZDIVO Z CDm 0.125 m | 1 | ZDIVO Z CDm | A | 1352HWa0000013259 | m3 | Celá stěna | Stávající | Zednické práce | ZDIVO Z CDm | yes | 1352Stě0000013260 | m3 | Stěna | 0 | 0.125 | 0.61 | 0.61 | 0.076 | 0.2 | 0.076 | 0.025 | 3.05
ZDIVO Z CDm | Půdorys 1.PP | ZDIVO Z CDm 0.125 m | 1 | ZDIVO Z CDm | A | 1352HWa0798456364 | m3 | Celá stěna | Stávající | Zednické práce | ZDIVO Z CDm | yes | 1352Stě0798456365 | m3 | Stěna | 0 | 0.125 | 0.61 | 0.61 | 0.076 | 0.2 | 0.076 | 0.025 | 3.05
ZDIVO Z CDm | Půdorys 1.PP | ZDIVO Z CDm 0.125 m | 1 | ZDIVO Z CDm | A | 1352HWa0798456374 | m3 | Celá stěna | Stávající | Zednické práce | ZDIVO Z CDm | yes | 1352Stě0798456375 | m3 | Stěna | 0 | 0.125 | 0.915 | 0.915 | 0.114 | 0.3 | 0.114 | 0.038 | 3.05
ZELEZOBETONOVÁ KCE | Půdorys 1.PP | ZELEZOBETONOVÁ KCE 0.62 m, LIGNOPOR 0.025 m, PÓROBETONOVÉ ZDIVO 0.08 m | 1 | ZELEZOBETONOVÁ KCE | A | 1352HWa0000003602 | m3 | Celá stěna | Stávající | Betonářské práce | ZELEZOBETONOVÁ KCE |  | 1352Stě0000003603 | m3 | Stěna | 0 | 0.725 | 66.133 | 66.133 | 39.289 | 15.985 | 39.289 | 11.487 | 4.1 | NEMSOK - Object Layer Attributes #2, 2D interakce: yes; Object Layer Attributes #2, Status: Stávající; Object Layer Attributes #2, Práce: Zateplovací systémy; Object Layer Attributes #2, Materiál: LIGNOPOR; Object Layer Attributes #2, Allright_Stavebni_dil_ID: 1352Stě0798456392; Object Layer Attributes #2, Jednotka: m2; Object Layer Attributes #2, Název_objektu: Stěna; Object Layer Attributes #3, 2D interakce: yes; Object Layer Attributes #3, Status: Stávající; Object Layer Attributes #3, Práce: Zednické práce; Object Layer Attributes #3, Materiál: PÓROBETONOVÉ ZDIVO; Object Layer Attributes #3, Allright_Stavebni_dil_ID: 1352Stě0798456393; Object Layer Attributes #3, Jednotka: m2; Object Layer Attributes #3, Název_objektu: Stěna; Pset_WallCommon - LoadBearing: yes
ZELEZOBETONOVÁ KCE | Půdorys 1.PP | ZELEZOBETONOVÁ KCE 0.2 m | 1 | ZELEZOBETONOVÁ KCE | A | 1352HWa0000003626 | m3 | Celá stěna | Stávající | Betonářské práce | ZELEZOBETONOVÁ KCE | yes | 1352Stě0000003627 | m3 | Stěna | 0 | 0.2 | 18.09 | 18.09 | 3.618 | 5.4 | 3.618 | 1.08 | 3.35
ZELEZOBETONOVÁ KCE | Půdorys 1.PP | ZELEZOBETONOVÁ KCE 0.2 m, LIGNOPOR 0.025 m, PÓROBETONOVÉ ZDIVO 0.08 m | 1 | ZELEZOBETONOVÁ KCE | A | 1352HWa0000003641 | m3 | Celá stěna | Stávající | Betonářské práce | ZELEZOBETONOVÁ KCE |  | 1352Stě0000003642 | m3 | Stěna | 0 | 0.305 | 3.585 | 3.585 | 0.967 | 0.777 | 0.967 | 0.28 | 4.1 | NEMSOK - Object Layer Attributes #2, 2D interakce: yes; Object Layer Attributes #2, Status: Stávající; Object Layer Attributes #2, Práce: Zateplovací systémy; Object Layer Attributes #2, Materiál: LIGNOPOR; Object Layer Attributes #2, Allright_Stavebni_dil_ID: 1352Stě0798456550; Object Layer Attributes #2, Jednotka: m2; Object Layer Attributes #2, Název_objektu: Stěna; Object Layer Attributes #3, 2D interakce: yes; Object Layer Attributes #3, Status: Stávající; Object Layer Attributes #3, Práce: Zednické práce; Object Layer Attributes #3, Materiál: PÓROBETONOVÉ ZDIVO; Object Layer Attributes #3, Allright_Stavebni_dil_ID: 1352Stě0798456551; Object Layer Attributes #3, Jednotka: m2; Object Layer Attributes #3, Název_objektu: Stěna; Pset_WallCommon - LoadBearing: yes
ZELEZOBETONOVÁ KCE | Půdorys 1.PP | ZELEZOBETONOVÁ KCE 0.620256 m, LIGNOPOR 0.025 m, PÓROBETONOVÉ ZDIVO 0.08 m | 1 | ZELEZOBETONOVÁ KCE | A | 1352HWa0000003610 | m3 | Celá stěna | Stávající | Betonářské práce | ZELEZOBETONOVÁ KCE |  | 1352Stě0000003611 | m3 | Stěna | 0 | 0.725 | 34.747 | 34.004 | 11.885 | 8.242 | 11.651 | 5.727 | 4.1 | NEMSOK - Object Layer Attributes #2, 2D interakce: yes; Object Layer Attributes #2, Status: Stávající; Object Layer Attributes #2, Práce: Zateplovací systémy; Object Layer Attributes #2, Materiál: LIGNOPOR; Object Layer Attributes #2, Allright_Stavebni_dil_ID: 1352Stě0798456760; Object Layer Attributes #2, Jednotka: m2; Object Layer Attributes #2, Název_objektu: Stěna; Object Layer Attributes #3, 2D interakce: yes; Object Layer Attributes #3, Status: Stávající; Object Layer Attributes #3, Práce: Zednické práce; Object Layer Attributes #3, Materiál: PÓROBETONOVÉ ZDIVO; Object Layer Attributes #3, Allright_Stavebni_dil_ID: 1352Stě0798456761; Object Layer Attributes #3, Jednotka: m2; Object Layer Attributes #3, Název_objektu: Stěna; Pset_WallCommon - LoadBearing: yes
ZELEZOBETONOVÁ KCE | Půdorys 1.PP | ZELEZOBETONOVÁ KCE 0.45 m, LIGNOPOR 0.025 m | 1 | ZELEZOBETONOVÁ KCE | A | 1352HWa0000007236 | m3 | Celá stěna | Stávající | Betonářské práce | ZELEZOBETONOVÁ KCE |  | 1352Stě0000007237 | m3 | Stěna | 0 | 0.475 | 9.322 | 9.295 | 4.428 | 8.25 | 4.097 | 3.919 | 1.13 | NEMSOK - Object Layer Attributes #2, 2D interakce: yes; Object Layer Attributes #2, Status: Stávající; Object Layer Attributes #2, Práce: Zateplovací systémy; Object Layer Attributes #2, Materiál: LIGNOPOR; Object Layer Attributes #2, Allright_Stavebni_dil_ID: 1352Stě0798457139; Object Layer Attributes #2, Jednotka: m2; Object Layer Attributes #2, Název_objektu: Stěna; Pset_WallCommon - LoadBearing: yes
ZDIVO Z CDm | Půdorys 1.PP | ZDIVO Z CDm 0.125 m | 1 | ZDIVO Z CDm | A | 1352HWa0798459053 | m3 | Celá stěna | Stávající | Zednické práce | ZDIVO Z CDm |  | 1352Stě0798459054 | m3 | Stěna | 0 | 0.125 | 3.05 | 3.05 | 0.381 | 1 | 0.381 | 0.125 | 3.05
ZDIVO Z CDm | Půdorys 1.PP | ZDIVO Z CDm 0.125 m | 1 | ZDIVO Z CDm | A | 1352HWa0798459080 | m3 | Celá stěna | Stávající | Zednické práce | ZDIVO Z CDm |  | 1352Stě0798459081 | m3 | Stěna | 0 | 0.125 | 0.976 | 0.976 | 0.122 | 0.32 | 0.122 | 0.04 | 3.05
ZDIVO Z CDm | Půdorys 1.PP | ZDIVO Z CDm 0.125 m | 1 | ZDIVO Z CDm | A | 1352HWa0798459186 | m3 | Celá stěna | Stávající | Zednické práce | ZDIVO Z CDm | yes | 1352Stě0798459187 | m3 | Stěna | 0 | 0.125 | 2.211 | 2.211 | 0.276 | 0.725 | 0.276 | 0.091 | 3.05
ZDIVO Z CDm | Půdorys 1.PP | ZDIVO Z CDm 0.125 m | 1 | ZDIVO Z CDm | A | 1352HWa0798459268 | m3 | Celá stěna | Stávající | Zednické práce | ZDIVO Z CDm | yes | 1352Stě0798459269 | m3 | Stěna | 0 | 0.125 | 1.601 | 1.601 | 0.2 | 0.525 | 0.2 | 0.066 | 3.05
ZDIVO Z CDm | Půdorys 1.PP | ZDIVO Z CDm 0.125 m | 1 | ZDIVO Z CDm | A | 1352HWa0798459253 | m3 | Celá stěna | Stávající | Zednické práce | ZDIVO Z CDm | yes | 1352Stě0798459254 | m3 | Stěna | 0 | 0.125 | 1.982 | 1.983 | 0.248 | 0.65 | 0.248 | 0.081 | 3.05
ZDIVO Z CDm | Půdorys 1.PP | ZDIVO Z CDm 0.125 m | 1 | ZDIVO Z CDm | A | 1352HWa0798459258 | m3 | Celá stěna | Stávající | Zednické práce | ZDIVO Z CDm | yes | 1352Stě0798459259 | m3 | Stěna | 0 | 0.125 | 1.601 | 1.601 | 0.2 | 0.525 | 0.2 | 0.066 | 3.05
ZDIVO Z CDm | Půdorys 1.PP | ZDIVO Z CDm 0.125 m | 1 | ZDIVO Z CDm | A | 1352HWa0798459280 | m3 | Celá stěna | Stávající | Zednické práce | ZDIVO Z CDm | yes | 1352Stě0798459281 | m3 | Stěna | 0 | 0.125 | 1.22 | 1.22 | 0.152 | 0.4 | 0.152 | 0.05 | 3.05
PÓROBETONOVÉ ZDIVO | Půdorys 1.PP | PÓROBETONOVÉ ZDIVO 0.1 m | 1 | PÓROBETONOVÉ ZDIVO | EI 120 | 1352HWa0798459305 | m3 | Celá stěna | Stávající | Zednické práce | PÓROBETONOVÉ ZDIVO |  | 1352Stě0798459306 | m2 | Stěna | 1.111 | 0.1 | 9.379 | 9.379 | 0.938 | 3.075 | 0.938 | 0.308 | 3.05 | Pset_WallCommon - AcousticRating: 37 dB
PÓROBETONOVÉ ZDIVO | Půdorys 1.PP | PÓROBETONOVÉ ZDIVO 0.1 m | 1 | PÓROBETONOVÉ ZDIVO | EI 120 | 1352HWa0798459314 | m3 | Celá stěna | Stávající | Zednické práce | PÓROBETONOVÉ ZDIVO |  | 1352Stě0798459315 | m2 | Stěna | 1.111 | 0.1 | 15.707 | 13.908 | 1.571 | 5.15 | 1.391 | 0.515 | 3.05 | Pset_WallCommon - AcousticRating: 37 dB
ZDIVO Z CDm | Půdorys 1.PP | ZDIVO Z CDm 0.125 m | 1 | ZDIVO Z CDm | A | 1352HWa0798459162 | m3 | Celá stěna | Stávající | Zednické práce | ZDIVO Z CDm | yes | 1352Stě0798459163 | m3 | Stěna | 0 | 0.125 | 1.601 | 1.121 | 0.2 | 0.525 | 0.14 | 0.066 | 3.05
ZDIVO Z CDm | Půdorys 1.PP | ZDIVO Z CDm 0.125 m | 1 | ZDIVO Z CDm | A | 1352HWa0798459155 | m3 | Celá stěna | Stávající | Zednické práce | ZDIVO Z CDm | yes | 1352Stě0798459156 | m3 | Stěna | 0 | 0.125 | 2.821 | 2.821 | 0.353 | 0.925 | 0.353 | 0.116 | 3.05
ZDIVO Z CDm | Půdorys 1.PP | ZDIVO Z CDm 0.125 m | 1 | ZDIVO Z CDm | A | 1352HWa0798459172 | m3 | Celá stěna | Stávající | Zednické práce | ZDIVO Z CDm | yes | 1352Stě0798459173 | m3 | Stěna | 0 | 0.125 | 2.44 | 2.44 | 0.305 | 0.8 | 0.305 | 0.1 | 3.05
ZDIVO Z CDm | Půdorys 1.PP | ZDIVO Z CDm 0.125 m | 1 | ZDIVO Z CDm | A | 1352HWa0798459435 | m3 | Celá stěna | Stávající | Zednické práce | ZDIVO Z CDm | yes | 1352Stě0798459436 | m3 | Stěna | 0 | 0.125 | 7.61 | 7.61 | 0.951 | 2.495 | 0.951 | 0.312 | 3.05
ZDIVO Z CDm | Půdorys 1.PP | ZDIVO Z CDm 0.125 m | 1 | ZDIVO Z CDm | A | 1352HWa0798459440 | m3 | Celá stěna | Stávající | Zednické práce | ZDIVO Z CDm | yes | 1352Stě0798459441 | m3 | Stěna | 0 | 0.125 | 7.991 | 7.991 | 0.999 | 2.62 | 0.999 | 0.327 | 3.05
SDK SVISLA CAST PODHLEDU | Půdorys 1.PP | SDK SVISLA CAST PODHLEDU 0.04 m | 1 | SDK SVISLA CAST PODHLEDU |  | 1352HWa0798459445 | m3 | Celá stěna | Stávající | Suché stavební práce | SDK SVISLA CAST PODHLEDU |  | 1352Stě0798459446 | m2 | Stěna |  | 0.04 | 0.72 | 0.72 | 0.029 | 3 | 0.029 | 0.12 | 0.24
SDK SVISLA CAST PODHLEDU | Půdorys 1.PP | SDK SVISLA CAST PODHLEDU 0.04 m | 1 | SDK SVISLA CAST PODHLEDU |  | 1352HWa0798459450 | m3 | Celá stěna | Stávající | Suché stavební práce | SDK SVISLA CAST PODHLEDU |  | 1352Stě0798459451 | m2 | Stěna |  | 0.04 | 0.744 | 0.744 | 0.03 | 3.1 | 0.03 | 0.124 | 0.24
ZDIVO Z CDm | Půdorys 1.PP | ZDIVO Z CDm 0.125 m | 1 | ZDIVO Z CDm | A | 1352HWa0798459495 | m3 | Celá stěna | Stávající | Zednické práce | ZDIVO Z CDm | yes | 1352Stě0798459496 | m3 | Stěna | 0 | 0.125 | 27.069 | 22.495 | 3.384 | 8.875 | 2.812 | 1.109 | 3.05
ZDIVO Z CDm | Půdorys 1.PP | ZDIVO Z CDm 0.2 m | 1 | ZDIVO Z CDm | A | 1352HWa0798459555 | m3 | Celá stěna | Stávající | Zednické práce | ZDIVO Z CDm |  | 1352Stě0798459556 | m3 | Stěna | 0 | 0.2 | 1.281 | 1.281 | 0.256 | 0.42 | 0.256 | 0.084 | 3.05
ZDIVO Z CDm | Půdorys 1.PP | ZDIVO Z CDm 0.225 m | 1 | ZDIVO Z CDm | A | 1352HWa0798459561 | m3 | Celá stěna | Stávající | Zednické práce | ZDIVO Z CDm |  | 1352Stě0798459562 | m3 | Stěna | 0 | 0.225 | 0.915 | 0.915 | 0.206 | 0.3 | 0.206 | 0.067 | 3.05
SDK SVISLA CAST PODHLEDU | Půdorys 1.PP | SDK SVISLA CAST PODHLEDU 0.04 m | 1 | SDK SVISLA CAST PODHLEDU |  | 1352HWa0798459591 | m3 | Celá stěna | Stávající | Suché stavební práce | SDK SVISLA CAST PODHLEDU |  | 1352Stě0798459592 | m2 | Stěna |  | 0.04 | 0.132 | 0.132 | 0.005 | 0.24 | 0.005 | 0.01 | 0.55
SDK SVISLA CAST PODHLEDU | Půdorys 1.PP | SDK SVISLA CAST PODHLEDU 0.04 m | 1 | SDK SVISLA CAST PODHLEDU |  | 1352HWa0798459596 | m3 | Celá stěna | Stávající | Suché stavební práce | SDK SVISLA CAST PODHLEDU |  | 1352Stě0798459597 | m2 | Stěna |  | 0.04 | 0.921 | 0.921 | 0.037 | 1.675 | 0.037 | 0.067 | 0.55
SDK SVISLA CAST PODHLEDU | Půdorys 1.PP | SDK SVISLA CAST PODHLEDU 0.04 m | 1 | SDK SVISLA CAST PODHLEDU |  | 1352HWa0798459611 | m3 | Celá stěna | Stávající | Suché stavební práce | SDK SVISLA CAST PODHLEDU |  | 1352Stě0798459612 | m2 | Stěna |  | 0.04 | 0.942 | 0.942 | 0.038 | 3.04 | 0.038 | 0.122 | 0.31
SDK SVISLA CAST PODHLEDU | Půdorys 1.PP | SDK SVISLA CAST PODHLEDU 0.04 m | 1 | SDK SVISLA CAST PODHLEDU |  | 1352HWa0798459616 | m3 | Celá stěna | Stávající | Suché stavební práce | SDK SVISLA CAST PODHLEDU |  | 1352Stě0798459617 | m2 | Stěna |  | 0.04 | 0.519 | 0.519 | 0.021 | 1.675 | 0.021 | 0.067 | 0.31
ZDIVO Z CDm | Půdorys 1.PP | ZDIVO Z CDm 0.125 m | 1 | ZDIVO Z CDm | A | 1352HWa0798459651 | m3 | Celá stěna | Stávající | Zednické práce | ZDIVO Z CDm | yes | 1352Stě0798459652 | m3 | Stěna | 0 | 0.125 | 10.065 | 9.345 | 1.258 | 3.3 | 1.168 | 0.413 | 3.05
ZDIVO Z CDm | Půdorys 1.PP | ZDIVO Z CDm 0.125 m | 1 | ZDIVO Z CDm | A | 1352HWa0798459661 | m3 | Celá stěna | Stávající | Zednické práce | ZDIVO Z CDm | yes | 1352Stě0798459662 | m3 | Stěna | 0 | 0.125 | 16.165 | 16.135 | 2.021 | 5.3 | 2.017 | 0.662 | 3.05
ZDIVO Z CDm | Půdorys 1.PP | ZDIVO Z CDm 0.125 m | 1 | ZDIVO Z CDm | A | 1352HWa0798459748 | m3 | Celá stěna | Stávající | Zednické práce | ZDIVO Z CDm | yes | 1352Stě0798459749 | m3 | Stěna | 0 | 0.125 | 4.422 | 3.009 | 0.553 | 1.45 | 0.376 | 0.181 | 3.05
ZDIVO Z CDm | Půdorys 1.PP | ZDIVO Z CDm 0.125 m | 1 | ZDIVO Z CDm | A | 1352HWa0798459758 | m3 | Celá stěna | Stávající | Zednické práce | ZDIVO Z CDm | yes | 1352Stě0798459759 | m3 | Stěna | 0 | 0.125 | 5.871 | 5.863 | 0.734 | 1.925 | 0.733 | 0.241 | 3.05
ZDIVO Z CDm | Půdorys 1.PP | ZDIVO Z CDm 0.125 m | 1 | ZDIVO Z CDm | A | 1352HWa0798459843 | m3 | Celá stěna | Stávající | Zednické práce | ZDIVO Z CDm | yes | 1352Stě0798459844 | m3 | Stěna | 0 | 0.125 | 3.812 | 3.813 | 0.477 | 1.25 | 0.477 | 0.156 | 3.05
ZDIVO Z CDm | Půdorys 1.PP | ZDIVO Z CDm 0.125 m | 1 | ZDIVO Z CDm | A | 1352HWa0798459889 | m3 | Celá stěna | Stávající | Zednické práce | ZDIVO Z CDm | yes | 1352Stě0798459892 | m3 | Stěna | 0 | 0.125 | 24.552 | 22.403 | 3.069 | 8.05 | 2.8 | 1.006 | 3.05
ZDIVO Z CDm | Půdorys 1.PP | ZDIVO Z CDm 0.125 m | 1 | ZDIVO Z CDm | A | 1352HWa0798459932 | m3 | Celá stěna | Stávající | Zednické práce | ZDIVO Z CDm | yes | 1352Stě0798459933 | m3 | Stěna | 0 | 0.125 | 15.402 | 11.565 | 1.925 | 5.05 | 1.446 | 0.631 | 3.05
ZDIVO Z CDm | Půdorys 1.PP | ZDIVO Z CDm 0.125 m | 1 | ZDIVO Z CDm | A | 1352HWa0798459771 | m3 | Celá stěna | Stávající | Zednické práce | ZDIVO Z CDm | yes | 1352Stě0798459772 | m3 | Stěna | 0 | 0.125 | 6.634 | 4.744 | 0.829 | 2.175 | 0.593 | 0.272 | 3.05
ZDIVO Z CDm | Půdorys 1.PP | ZDIVO Z CDm 0.225 m | 1 | ZDIVO Z CDm | A | 1352HWa0798460578 | m3 | Celá stěna | Stávající | Zednické práce | ZDIVO Z CDm |  | 1352Stě0798460580 | m3 | Stěna | 0 | 0.225 | 1.83 | 1.83 | 0.412 | 0.6 | 0.412 | 0.135 | 3.05
SDK SVISLA CAST PODHLEDU | Půdorys 1.PP | SDK SVISLA CAST PODHLEDU 0.04 m | 1 | SDK SVISLA CAST PODHLEDU |  | 1352HWa0798460708 | m3 | Celá stěna | Stávající | Suché stavební práce | SDK SVISLA CAST PODHLEDU |  | 1352Stě0798460709 | m2 | Stěna |  | 0.04 | 0.467 | 0.467 | 0.019 | 0.64 | 0.019 | 0.026 | 0.73
SDK SVISLA CAST PODHLEDU | Půdorys 1.PP | SDK SVISLA CAST PODHLEDU 0.04 m | 1 | SDK SVISLA CAST PODHLEDU |  | 1352HWa0798460718 | m3 | Celá stěna | Stávající | Suché stavební práce | SDK SVISLA CAST PODHLEDU |  | 1352Stě0798460719 | m2 | Stěna |  | 0.04 | 0.548 | 0.548 | 0.022 | 0.75 | 0.022 | 0.03 | 0.73
ZDIVO Z CDm | Půdorys 1.PP | ZDIVO Z CDm 0.125 m | 1 | ZDIVO Z CDm | A | 1352HWa0798459811 | m3 | Celá stěna | Stávající | Zednické práce | ZDIVO Z CDm | yes | 1352Stě0798459812 | m3 | Stěna | 0 | 0.125 | 15.402 | 10.151 | 1.925 | 5.05 | 1.269 | 0.631 | 3.05
SDK SVISLA CAST PODHLEDU | Půdorys 1.PP | SDK SVISLA CAST PODHLEDU 0.04 m | 1 | SDK SVISLA CAST PODHLEDU |  | 1352HWa0798460762 | m3 | Celá stěna | Stávající | Suché stavební práce | SDK SVISLA CAST PODHLEDU | no | 1352Stě0798460763 | m2 | Stěna |  | 0.04 | 0.058 | 0.058 | 0.002 | 0.34 | 0.002 | 0.014 | 0.17
SDK SVISLA CAST PODHLEDU | Půdorys 1.PP | SDK SVISLA CAST PODHLEDU 0.04 m | 1 | SDK SVISLA CAST PODHLEDU |  | 1352HWa0798460772 | m3 | Celá stěna | Stávající | Suché stavební práce | SDK SVISLA CAST PODHLEDU | no | 1352Stě0798460773 | m2 | Stěna |  | 0.04 | 0.034 | 0.034 | 0.001 | 0.2 | 0.001 | 0.008 | 0.17
ZDIVO Z CDm | Půdorys 1.PP | ZDIVO Z CDm 0.125 m | 1 | ZDIVO Z CDm | A | 1352HWa0798443512 | m3 | Celá stěna | Stávající | Zednické práce | ZDIVO Z CDm | yes | 1352Stě0798443513 | m3 | Stěna | 0 | 0.125 | 2.669 | 2.669 | 0.334 | 0.875 | 0.334 | 0.109 | 3.05
ZDIVO Z CDm | Půdorys 1.PP | ZDIVO Z CDm 0.125 m | 1 | ZDIVO Z CDm | A | 1352HWa0798437017 | m3 | Celá stěna | Stávající | Zednické práce | ZDIVO Z CDm | yes | 1352Stě0798437018 | m3 | Stěna | 0 | 0.125 | 1.144 | 1.144 | 0.143 | 0.375 | 0.143 | 0.047 | 3.05
ZDIVO Z CDm | Půdorys 1.PP | ZDIVO Z CDm 0.25 m | 1 | ZDIVO Z CDm | A | 1352HWa0798451710 | m3 | Celá stěna | Stávající | Zednické práce | ZDIVO Z CDm |  | 1352Stě0798451711 | m3 | Stěna | 0 | 0.25 | 3.66 | 3.66 | 0.915 | 1.2 | 0.915 | 0.3 | 3.05
ZDIVO Z CDm | Půdorys 1.PP | ZDIVO Z CDm 0.25 m | 1 | ZDIVO Z CDm | A | 1352HWa0798451715 | m3 | Celá stěna | Stávající | Zednické práce | ZDIVO Z CDm |  | 1352Stě0798451716 | m3 | Stěna | 0 | 0.25 | 2.592 | 2.593 | 0.648 | 0.85 | 0.648 | 0.213 | 3.05
ZDIVO Z CDm | Půdorys 1.PP | ZDIVO Z CDm 0.25 m | 1 | ZDIVO Z CDm | A | 1352HWa0798451725 | m3 | Celá stěna | Stávající | Zednické práce | ZDIVO Z CDm |  | 1352Stě0798451726 | m3 | Stěna | 0 | 0.25 | 2.897 | 2.898 | 0.724 | 0.95 | 0.724 | 0.237 | 3.05
ZDIVO Z CDm | Půdorys 1.PP | ZDIVO Z CDm 0.35 m | 1 | ZDIVO Z CDm | A | 1352HWa0798451737 | m3 | Celá stěna | Stávající | Zednické práce | ZDIVO Z CDm |  | 1352Stě0798451738 | m3 | Stěna | 0 | 0.35 | 1.83 | 1.83 | 0.641 | 0.6 | 0.641 | 0.21 | 3.05
ZELEZOBETONOVÁ KCE | Půdorys 1.PP | PÓROBETONOVÉ ZDIVO 0.1 m |  | ZELEZOBETONOVÁ KCE | A | 1352HWa0798451824 | m3 | Celá stěna | Stávající | Zednické práce | PÓROBETONOVÉ ZDIVO |  | 1352Stě0798451825 | m2 | Stěna | 0 | 0.1 | 3.935 | 3.935 | 0.393 | 1.29 | 0.393 | 0.129 | 3.05 | Pset_WallCommon - LoadBearing: yes
ZELEZOBETONOVÁ KCE | Půdorys 1.PP | PÓROBETONOVÉ ZDIVO 0.1 m |  | ZELEZOBETONOVÁ KCE | A | 1352HWa0798451832 | m3 | Celá stěna | Stávající | Zednické práce | PÓROBETONOVÉ ZDIVO |  | 1352Stě0798451833 | m2 | Stěna | 0 | 0.1 | 3.66 | 3.66 | 0.366 | 1.2 | 0.366 | 0.12 | 3.05 | Pset_WallCommon - LoadBearing: yes
ZELEZOBETONOVÁ KCE | Půdorys 1.PP | PÓROBETONOVÉ ZDIVO 0.1 m |  | ZELEZOBETONOVÁ KCE | A | 1352HWa0798451847 | m3 | Celá stěna | Stávající | Zednické práce | PÓROBETONOVÉ ZDIVO |  | 1352Stě0798451848 | m2 | Stěna | 0 | 0.1 | 3.629 | 3.63 | 0.363 | 1.19 | 0.363 | 0.119 | 3.05 | Pset_WallCommon - LoadBearing: yes
ZDIVO Z CDm | Půdorys 1.PP | ZDIVO Z CDm 0.125 m | 1 | ZDIVO Z CDm | A | 1352HWa0798437055 | m3 | Celá stěna | Stávající | Zednické práce | ZDIVO Z CDm | yes | 1352Stě0798437056 | m3 | Stěna | 0 | 0.125 | 6.313 | 3.043 | 0.789 | 2.07 | 0.38 | 0.259 | 3.05
ZDIVO Z CDm | Půdorys 1.PP | ZDIVO Z CDm 0.125 m | 1 | ZDIVO Z CDm | A | 1352HWa0798465957 | m3 | Celá stěna | Stávající | Zednické práce | ZDIVO Z CDm | yes | 1352Stě0798466019 | m3 | Stěna | 0 | 0.125 | 3.965 | 3.965 | 0.496 | 1.3 | 0.496 | 0.162 | 3.05
ZDIVO Z CDm | Půdorys 1.PP | ZDIVO Z CDm 0.125 m | 1 | ZDIVO Z CDm | A | 1352HWa0798465959 | m3 | Celá stěna | Stávající | Zednické práce | ZDIVO Z CDm | yes | 1352Stě0798465994 | m3 | Stěna | 0 | 0.125 | 34.694 | 28.277 | 4.337 | 11.375 | 3.535 | 1.422 | 3.05
ZDIVO Z CDm | Půdorys 1.PP | ZDIVO Z CDm 0.125 m | 1 | ZDIVO Z CDm | A | 1352HWa0798465960 | m3 | Celá stěna | Stávající | Zednické práce | ZDIVO Z CDm | yes | 1352Stě0798466015 | m3 | Stěna | 0 | 0.125 | 3.202 | 3.203 | 0.4 | 1.05 | 0.4 | 0.131 | 3.05
ZDIVO Z CDm | Půdorys 1.PP | ZDIVO Z CDm 0.25 m | 1 | ZDIVO Z CDm | A | 1352HWa0798465979 | m3 | Celá stěna | Stávající | Zednické práce | ZDIVO Z CDm | yes | 1352Stě0798466013 | m3 | Stěna | 0 | 0.25 | 13.382 | 13.382 | 3.345 | 4.388 | 3.345 | 1.097 | 3.05
BETONOVÁ KCE S BARYTEM | Půdorys 1.PP | BETONOVÁ KCE S BARYTEM 0.2 m |  | BETONOVÁ KCE S BARYTEM | A | 1352HWa0798453715 | m3 | Celá stěna | Stávající | Betonářské práce | BETONOVÁ KCE S BARYTEM |  | 1352Stě0798453716 | m3 | Stěna | 0 | 0.2 | 5.871 | 5.773 | 1.174 | 1.925 | 1.155 | 0.385 | 3.05 | Pset_WallCommon - LoadBearing: yes
BETONOVÁ KCE S BARYTEM | Půdorys 1.PP | BETONOVÁ KCE S BARYTEM 0.2 m |  | BETONOVÁ KCE S BARYTEM | A | 1352HWa0798462545 | m3 | Celá stěna | Stávající | Betonářské práce | BETONOVÁ KCE S BARYTEM |  | 1352Stě0798462547 | m3 | Stěna | 0 | 0.2 | 0.763 | 0.763 | 0.153 | 0.25 | 0.153 | 0.05 | 3.05 | Pset_WallCommon - LoadBearing: yes
ZELEZOBETONOVÁ KCE | Půdorys 1.PP | ZELEZOBETONOVÁ KCE 0.3 m |  | ZELEZOBETONOVÁ KCE | A | 1352HWa0000004646 | m3 | Celá stěna | Stávající | Betonářské práce | ZELEZOBETONOVÁ KCE | no | 1352Stě0000004647 | m3 | Stěna | 0 | 0.3 | 1.286 | 1.286 | 0.386 | 0.525 | 0.386 | 0.157 | 2.45 | Pset_WallCommon - LoadBearing: yes
ZELEZOBETONOVÁ KCE | Půdorys 1.PP | ZELEZOBETONOVÁ KCE 0.3 m |  | ZELEZOBETONOVÁ KCE | A | 1352HWa0798466912 | m3 | Celá stěna | Stávající | Betonářské práce | ZELEZOBETONOVÁ KCE | no | 1352Stě0798466916 | m3 | Stěna | 0 | 0.3 | 2.45 | 2.45 | 0.735 | 1 | 0.735 | 0.3 | 2.45 | Pset_WallCommon - LoadBearing: yes
ZDIVO Z CDm | Půdorys 1.PP | ZDIVO Z CDm 0.125 m |  | ZDIVO Z CDm | A | 1352HWa0798466956 | m3 | Celá stěna | Stávající | Zednické práce | ZDIVO Z CDm | no | 1352Stě0798466957 | m3 | Stěna | 0 | 0.125 | 4.41 | 4.41 | 0.551 | 1.8 | 0.551 | 0.225 | 2.45
ZELEZOBETONOVÁ KCE | Půdorys 1.PP | ZELEZOBETONOVÁ KCE 0.3 m |  | ZELEZOBETONOVÁ KCE | A | 1352HWa0798466913 | m3 | Celá stěna | Stávající | Betonářské práce | ZELEZOBETONOVÁ KCE | no | 1352Stě0798466917 | m3 | Stěna | 0 | 0.3 | 2.45 | 2.45 | 0.735 | 1 | 0.735 | 0.3 | 2.45 | Pset_WallCommon - LoadBearing: yes
ZELEZOBETONOVÁ KCE | Půdorys 1.PP | ZELEZOBETONOVÁ KCE 0.3 m |  | ZELEZOBETONOVÁ KCE | A | 1352HWa0000004659 | m3 | Celá stěna | Stávající | Betonářské práce | ZELEZOBETONOVÁ KCE | no | 1352Stě0000004660 | m3 | Stěna | 0 | 0.3 | 1.286 | 1.286 | 0.386 | 0.525 | 0.386 | 0.157 | 2.45 | Pset_WallCommon - LoadBearing: yes
ZELEZOBETONOVÁ KCE | Půdorys 1.PP | ZELEZOBETONOVÁ KCE 0.2 m, LIGNOPOR 0.025 m, PÓROBETONOVÉ ZDIVO 0.08 m |  | ZELEZOBETONOVÁ KCE | A | 1352HWa0798432204 | m3 | Celá stěna | Stávající | Betonářské práce | ZELEZOBETONOVÁ KCE |  | 1352Stě0798432222 | m3 | Stěna | 0 | 0.305 | 42.377 | 35.771 | 10.711 | 12.607 | 9.145 | 3.849 | 3.35 | NEMSOK - Object Layer Attributes #2, 2D interakce: yes; Object Layer Attributes #2, Status: Stávající; Object Layer Attributes #2, Práce: Zateplovací systémy; Object Layer Attributes #2, Materiál: LIGNOPOR; Object Layer Attributes #2, Allright_Stavebni_dil_ID: 1352Stě0798432221; Object Layer Attributes #2, Jednotka: m2; Object Layer Attributes #2, Název_objektu: Stěna; Object Layer Attributes #3, 2D interakce: yes; Object Layer Attributes #3, Status: Stávající; Object Layer Attributes #3, Práce: Zednické práce; Object Layer Attributes #3, Materiál: PÓROBETONOVÉ ZDIVO; Object Layer Attributes #3, Allright_Stavebni_dil_ID: 1352Stě0798432318; Object Layer Attributes #3, Jednotka: m2; Object Layer Attributes #3, Název_objektu: Stěna; Pset_WallCommon - LoadBearing: yes
ZDIVO Z CDm | Půdorys 1.PP | ZDIVO Z CDm 0.125 m | 1 | ZDIVO Z CDm | A | 1352HWa0798441276 | m3 | Celá stěna | Stávající | Zednické práce | ZDIVO Z CDm | yes | 1352Stě0798441277 | m3 | Stěna | 0 | 0.125 | 8.464 | 5.839 | 1.058 | 2.775 | 0.73 | 0.347 | 3.05
ZDIVO Z CDm | Půdorys 1.PP | ZDIVO Z CDm 0.125 m | 1 | ZDIVO Z CDm | A | 1352HWa0798469349 | m3 | Celá stěna | Stávající | Zednické práce | ZDIVO Z CDm | yes | 1352Stě0798469360 | m3 | Stěna | 0 | 0.125 | 2.211 | 1.731 | 0.276 | 0.725 | 0.216 | 0.091 | 3.05
ZDIVO Z CDm | Půdorys 1.PP | ZDIVO Z CDm 0.125 m | 1 | ZDIVO Z CDm | A | 1352HWa0798469353 | m3 | Celá stěna | Stávající | Zednické práce | ZDIVO Z CDm | yes | 1352Stě0798469355 | m3 | Stěna | 0 | 0.125 | 1.22 | 1.22 | 0.152 | 0.4 | 0.152 | 0.05 | 3.05
ZDIVO Z CDm | Půdorys 1.PP | ZDIVO Z CDm 0.125 m | 1 | ZDIVO Z CDm | A | 1352HWa0798469351 | m3 | Celá stěna | Stávající | Zednické práce | ZDIVO Z CDm | yes | 1352Stě0798469359 | m3 | Stěna | 0 | 0.125 | 3.05 | 3.05 | 0.381 | 1 | 0.381 | 0.125 | 3.05
PÓROBETONOVÉ ZDIVO | Půdorys 1.PP | PÓROBETONOVÉ ZDIVO 0.1 m | 1 | PÓROBETONOVÉ ZDIVO | EI 120 | 1352HWa0798469495 | m3 | Celá stěna | Stávající | Zednické práce | PÓROBETONOVÉ ZDIVO |  | 1352Stě0798469503 | m2 | Stěna | 1.111 | 0.1 | 16.317 | 11.818 | 1.632 | 5.35 | 1.182 | 0.535 | 3.05 | Pset_WallCommon - AcousticRating: 37 dB
ZELEZOBETONOVÁ KCE | Půdorys 1.PP | ZELEZOBETONOVÁ KCE 0.2 m |  | ZELEZOBETONOVÁ KCE | A | 1352HWa0798428096 | m3 | Celá stěna | Stávající | Betonářské práce | ZELEZOBETONOVÁ KCE | no | 1352Stě0798428097 | m3 | Stěna | 0 | 0.2 | 16.75 | 14.592 | 3.35 | 5 | 2.918 | 1 | 3.35 | Pset_WallCommon - LoadBearing: yes
ZDIVO Z CDm | Půdorys 1.PP | ZDIVO Z CDm 0.125 m |  | ZDIVO Z CDm | A | 1352HWa0798470269 | m3 | Celá stěna | Stávající | Zednické práce | ZDIVO Z CDm | yes | 1352Stě0798470272 | m3 | Stěna | 0 | 0.125 | 14.564 | 14.564 | 1.82 | 4.775 | 1.82 | 0.597 | 3.05
ZDIVO Z CDm | Půdorys 1.PP | ZDIVO Z CDm 0.125 m | 1 | ZDIVO Z CDm | A | 1352HWa0798470293 | m3 | Celá stěna | Stávající | Zednické práce | ZDIVO Z CDm | yes | 1352Stě0798470294 | m3 | Stěna | 0 | 0.125 | 16.775 | 17.08 | 2.097 | 5.5 | 2.097 | 0.688 | 3.05
ZDIVO Z CDm | Půdorys 1.PP | ZDIVO Z CDm 0.125 m | 1 | ZDIVO Z CDm | A | 1352HWa0798470339 | m3 | Celá stěna | Stávající | Zednické práce | ZDIVO Z CDm | yes | 1352Stě0798470340 | m3 | Stěna | 0 | 0.125 | 2.44 | 1.72 | 0.305 | 0.8 | 0.215 | 0.1 | 3.05
ZDIVO Z CDm | Půdorys 1.PP | ZDIVO Z CDm 0.125 m | 1 | ZDIVO Z CDm | A | 1352HWa0798470349 | m3 | Celá stěna | Stávající | Zednické práce | ZDIVO Z CDm | yes | 1352Stě0798470350 | m3 | Stěna | 0 | 0.125 | 2.745 | 2.745 | 0.343 | 0.9 | 0.343 | 0.112 | 3.05
ZDIVO Z CDm | Půdorys 1.PP | ZDIVO Z CDm 0.125 m | 1 | ZDIVO Z CDm | A | 1352HWa0798470509 | m3 | Celá stěna | Stávající | Zednické práce | ZDIVO Z CDm | yes | 1352Stě0798470510 | m3 | Stěna | 0 | 0.125 | 29.89 | 20.574 | 3.736 | 9.8 | 2.663 | 1.225 | 3.05
ZDIVO Z CDm | Půdorys 1.PP | ZDIVO Z CDm 0.125 m | 1 | ZDIVO Z CDm | A | 1352HWa0798470519 | m3 | Celá stěna | Stávající | Zednické práce | ZDIVO Z CDm | yes | 1352Stě0798470520 | m3 | Stěna | 0 | 0.125 | 1.372 | 1.373 | 0.172 | 0.45 | 0.172 | 0.056 | 3.05
ZDIVO Z CDm | Půdorys 1.PP | ZDIVO Z CDm 0.125 m | 1 | ZDIVO Z CDm | A | 1352HWa0798470558 | m3 | Celá stěna | Stávající | Zednické práce | ZDIVO Z CDm | yes | 1352Stě0798470560 | m3 | Stěna | 0 | 0.125 | 1.372 | 1.373 | 0.172 | 0.45 | 0.172 | 0.056 | 3.05
ZDIVO Z CDm | Půdorys 1.PP | ZDIVO Z CDm 0.125 m | 1 | ZDIVO Z CDm | A | 1352HWa0798470569 | m3 | Celá stěna | Stávající | Zednické práce | ZDIVO Z CDm | yes | 1352Stě0798470571 | m3 | Stěna | 0 | 0.125 | 1.372 | 1.373 | 0.172 | 0.45 | 0.172 | 0.056 | 3.05
ZDIVO Z CDm | Půdorys 1.PP | ZDIVO Z CDm 0.125 m | 1 | ZDIVO Z CDm | A | 1352HWa0798470578 | m3 | Celá stěna | Stávající | Zednické práce | ZDIVO Z CDm | yes | 1352Stě0798470580 | m3 | Stěna | 0 | 0.125 | 1.372 | 1.373 | 0.172 | 0.45 | 0.172 | 0.056 | 3.05
PÓROBETONOVÉ ZDIVO | Půdorys 1.PP | PÓROBETONOVÉ ZDIVO 0.1 m | 1 | PÓROBETONOVÉ ZDIVO | EI 120 | 1352HWa0798470589 | m3 | Celá stěna | Stávající | Zednické práce | PÓROBETONOVÉ ZDIVO |  | 1352Stě0798470590 | m2 | Stěna | 1.111 | 0.1 | 3.66 | 3.66 | 0.366 | 1.2 | 0.366 | 0.12 | 3.05 | Pset_WallCommon - AcousticRating: 37 dB
PÓROBETONOVÉ ZDIVO | Půdorys 1.PP | PÓROBETONOVÉ ZDIVO 0.1 m | 1 | PÓROBETONOVÉ ZDIVO | EI 120 | 1352HWa0798470602 | m3 | Celá stěna | Stávající | Zednické práce | PÓROBETONOVÉ ZDIVO |  | 1352Stě0798470603 | m2 | Stěna | 1.111 | 0.1 | 9.455 | 9.455 | 0.946 | 3.1 | 0.946 | 0.31 | 3.05 | Pset_WallCommon - AcousticRating: 37 dB
PÓROBETONOVÉ ZDIVO | Půdorys 1.PP | PÓROBETONOVÉ ZDIVO 0.1 m | 1 | PÓROBETONOVÉ ZDIVO | EI 120 | 1352HWa0798470658 | m3 | Celá stěna | Stávající | Zednické práce | PÓROBETONOVÉ ZDIVO |  | 1352Stě0798470659 | m2 | Stěna | 1.111 | 0.1 | 0.976 | 0.976 | 0.098 | 0.32 | 0.098 | 0.032 | 3.05 | Pset_WallCommon - AcousticRating: 37 dB
ZDIVO Z CDm | Půdorys 1.PP | ZDIVO Z CDm 0.125 m | 1 | ZDIVO Z CDm | A | 1352HWa0798470674 | m3 | Celá stěna | Stávající | Zednické práce | ZDIVO Z CDm | yes | 1352Stě0798470675 | m3 | Stěna | 0 | 0.125 | 0.671 | 0.671 | 0.084 | 0.22 | 0.084 | 0.027 | 3.05
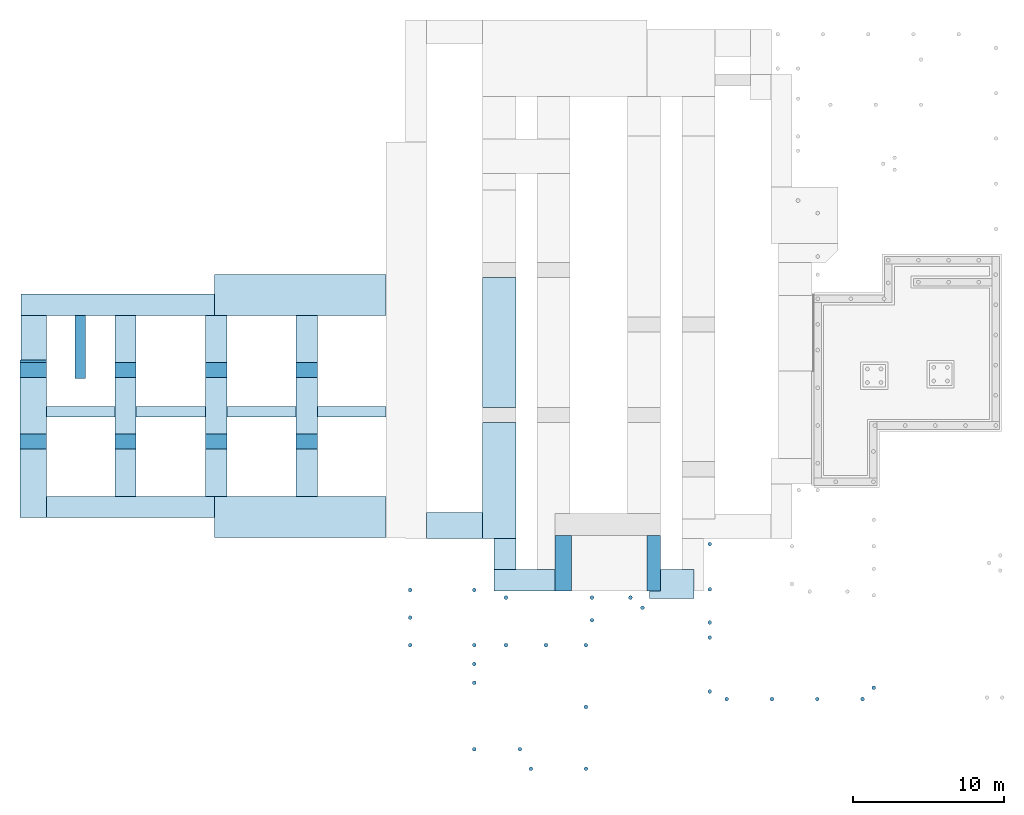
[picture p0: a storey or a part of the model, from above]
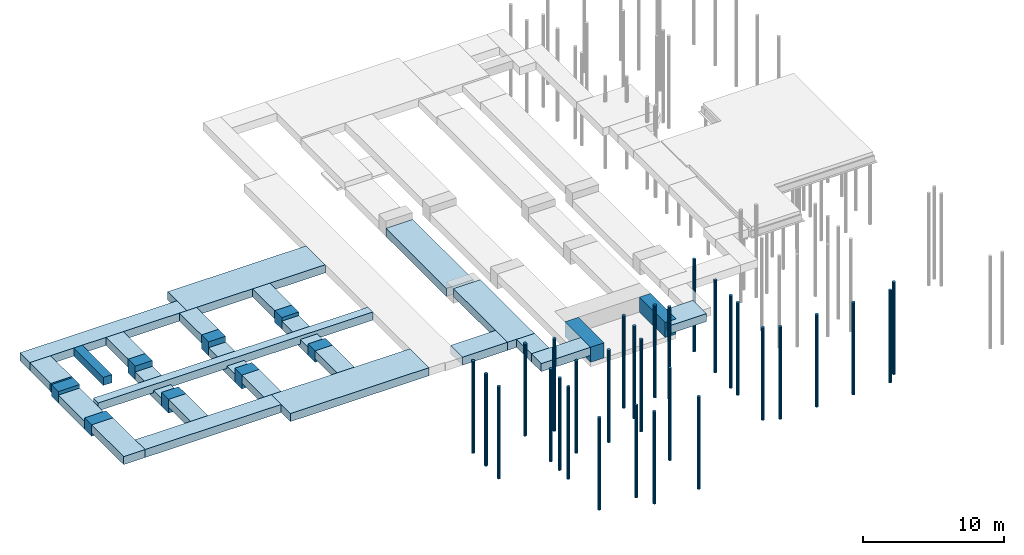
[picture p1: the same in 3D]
Properties of the parts of a building model (IFC4), part 26 of 45

# IfcWall (2385)
Name | In | Material | Faktor | Označení | Požární odolnost | Allright_Stavebni_dil_ID | Jednotka | Název_objektu | Object Layer Attributes #1, Status | Object Layer Attributes #1, Práce | Object Layer Attributes #1, Materiál | Object Layer Attributes #1, Staticky nosná konstrukce | Object Layer Attributes #1, Allright_Stavebni_dil_ID | Object Layer Attributes #1, Jednotka | Object Layer Attributes #1, Název_objektu | ThermalTransmittance (W/K/m2) | Width (m) | GrossSideArea (m2) | NetSideArea (m2) | GrossVolume (m3) | Length (m) | NetVolume (m3) | GrossFootprintArea (m2) | Height (m)
ZDIVO Z CDm | Půdorys 1.PP | ZDIVO Z CDm 0.125 m | 1 | ZDIVO Z CDm | A | 1352HWa0798470685 | m3 | Celá stěna | Stávající | Zednické práce | ZDIVO Z CDm | yes | 1352Stě0798470686 | m3 | Stěna | 0 | 0.125 | 15.555 | 14.355 | 1.944 | 5.1 | 1.794 | 0.637 | 3.05
ZDIVO Z CDm | Půdorys 1.PP | ZDIVO Z CDm 0.125 m | 1 | ZDIVO Z CDm | A | 1352HWa0798470524 | m3 | Celá stěna | Stávající | Zednické práce | ZDIVO Z CDm | yes | 1352Stě0798470525 | m3 | Stěna | 0 | 0.125 | 40.413 | 36.472 | 5.052 | 13.25 | 4.559 | 1.656 | 3.05
ZDIVO Z CDm | Půdorys 1.PP | ZDIVO Z CDm 0.125 m | 1 | ZDIVO Z CDm | A | 1352HWa0798428005 | m3 | Celá stěna | Stávající | Zednické práce | ZDIVO Z CDm | yes | 1352Stě0798428006 | m3 | Stěna | 0 | 0.125 | 6.481 | 3.35 | 0.81 | 2.125 | 0.419 | 0.266 | 3.05
ZDIVO Z CDm | Půdorys 1.PP | ZDIVO Z CDm 0.225 m | 1 | ZDIVO Z CDm | A | 1352HWa0798471096 | m3 | Celá stěna | Stávající | Zednické práce | ZDIVO Z CDm | yes | 1352Stě0798471097 | m3 | Stěna | 0 | 0.225 | 1.754 | 1.754 | 0.395 | 0.575 | 0.395 | 0.129 | 3.05
ZDIVO Z CDm | Půdorys 1.PP | ZDIVO Z CDm 0.125 m | 1 | ZDIVO Z CDm | A | 1352HWa0798471221 | m3 | Celá stěna | Stávající | Zednické práce | ZDIVO Z CDm | yes | 1352Stě0798471222 | m3 | Stěna | 0 | 0.125 | 2.745 | 2.745 | 0.343 | 0.9 | 0.343 | 0.113 | 3.05
ZDIVO Z CDm | Půdorys 1.PP | ZDIVO Z CDm 0.125 m | 1 | ZDIVO Z CDm | A | 1352HWa0798471211 | m3 | Celá stěna | Stávající | Zednické práce | ZDIVO Z CDm | yes | 1352Stě0798471212 | m3 | Stěna | 0 | 0.125 | 5.795 | 4.381 | 0.724 | 1.9 | 0.548 | 0.237 | 3.05
ZDIVO Z CDm | Půdorys 1.PP | ZDIVO Z CDm 0.125 m | 1 | ZDIVO Z CDm | A | 1352HWa0798471235 | m3 | Celá stěna | Stávající | Zednické práce | ZDIVO Z CDm | yes | 1352Stě0798471236 | m3 | Stěna | 0 | 0.125 | 3.279 | 3.279 | 0.41 | 1.075 | 0.41 | 0.134 | 3.05
ZDIVO Z CDm | Půdorys 1.PP | ZDIVO Z CDm 0.125 m | 1 | ZDIVO Z CDm | A | 1352HWa0798456354 | m3 | Celá stěna | Stávající | Zednické práce | ZDIVO Z CDm | yes | 1352Stě0798456355 | m3 | Stěna | 0 | 0.125 | 2.745 | 2.745 | 0.343 | 0.9 | 0.343 | 0.113 | 3.05
ZDIVO Z CDm | Půdorys 1.PP | ZDIVO Z CDm 0.225 m | 1 | ZDIVO Z CDm | A | 1352HWa0798471505 | m3 | Celá stěna | Stávající | Zednické práce | ZDIVO Z CDm | yes | 1352Stě0798471506 | m3 | Stěna | 0 | 0.225 | 1.22 | 1.22 | 0.275 | 0.4 | 0.275 | 0.09 | 3.05
ZDIVO Z CDm | Půdorys 1.PP | ZDIVO Z CDm 0.125 m | 1 | ZDIVO Z CDm | A | 1352HWa0798471437 | m3 | Celá stěna | Stávající | Zednické práce | ZDIVO Z CDm | yes | 1352Stě0798471450 | m3 | Stěna | 0 | 0.125 | 17.08 | 13.444 | 2.135 | 5.6 | 1.681 | 0.7 | 3.05
ZDIVO Z CDm | Půdorys 1.PP | ZDIVO Z CDm 0.225 m | 1 | ZDIVO Z CDm | A | 1352HWa0798471578 | m3 | Celá stěna | Stávající | Zednické práce | ZDIVO Z CDm | yes | 1352Stě0798471580 | m3 | Stěna | 0 | 0.225 | 1.22 | 1.22 | 0.275 | 0.4 | 0.275 | 0.09 | 3.05
ZDIVO Z CDm | Půdorys 1.PP | ZDIVO Z CDm 0.125 m | 1 | ZDIVO Z CDm | A | 1352HWa0798471520 | m3 | Celá stěna | Stávající | Zednické práce | ZDIVO Z CDm | yes | 1352Stě0798471539 | m3 | Stěna | 0 | 0.125 | 13.42 | 10.996 | 1.677 | 4.4 | 1.374 | 0.55 | 3.05
ZDIVO Z CDm | Půdorys 1.PP | ZDIVO Z CDm 0.125 m | 1 | ZDIVO Z CDm | A | 1352HWa0798471593 | m3 | Celá stěna | Stávající | Zednické práce | ZDIVO Z CDm | yes | 1352Stě0798471612 | m3 | Stěna | 0 | 0.125 | 22.494 | 19.35 | 2.812 | 7.375 | 2.419 | 0.922 | 3.05
ZDIVO Z CDm | Půdorys 1.PP | ZDIVO Z CDm 0.225 m | 1 | ZDIVO Z CDm | A | 1352HWa0798471641 | m3 | Celá stěna | Stávající | Zednické práce | ZDIVO Z CDm | yes | 1352Stě0798471643 | m3 | Stěna | 0 | 0.225 | 1.22 | 1.22 | 0.275 | 0.4 | 0.275 | 0.09 | 3.05
SDK SVISLA CAST PODHLEDU | Půdorys 1.PP | SDK SVISLA CAST PODHLEDU 0.04 m | 1 | SDK SVISLA CAST PODHLEDU |  | 1352HWa0798471811 | m3 | Celá stěna | Stávající | Suché stavební práce | SDK SVISLA CAST PODHLEDU | no | 1352Stě0798471812 | m2 | Stěna |  | 0.04 | 2.202 | 2.202 | 0.088 | 7.34 | 0.088 | 0.294 | 0.3
SDK SVISLA CAST PODHLEDU | Půdorys 1.PP | SDK SVISLA CAST PODHLEDU 0.04 m | 1 | SDK SVISLA CAST PODHLEDU |  | 1352HWa0798471816 | m3 | Celá stěna | Stávající | Suché stavební práce | SDK SVISLA CAST PODHLEDU | no | 1352Stě0798471817 | m2 | Stěna |  | 0.04 | 1.62 | 1.62 | 0.065 | 5.4 | 0.065 | 0.216 | 0.3
SDK SVISLA CAST PODHLEDU | Půdorys 1.PP | SDK SVISLA CAST PODHLEDU 0.04 m | 1 | SDK SVISLA CAST PODHLEDU |  | 1352HWa0798471821 | m3 | Celá stěna | Stávající | Suché stavební práce | SDK SVISLA CAST PODHLEDU | no | 1352Stě0798471822 | m2 | Stěna |  | 0.04 | 1.774 | 1.775 | 0.071 | 5.915 | 0.071 | 0.237 | 0.3
ZDIVO Z CDm | Půdorys 1.PP | ZDIVO Z CDm 0.125 m | 1 | ZDIVO Z CDm | A | 1352HWa0798460588 | m3 | Celá stěna | Stávající | Zednické práce | ZDIVO Z CDm | yes | 1352Stě0798460590 | m3 | Stěna | 0 | 0.125 | 7.091 | 4.667 | 0.886 | 2.325 | 0.583 | 0.291 | 3.05
ZDIVO Z CDm | Půdorys 1.PP | ZDIVO Z CDm 0.125 m | 1 | ZDIVO Z CDm | A | 1352HWa0798472005 | m3 | Celá stěna | Stávající | Zednické práce | ZDIVO Z CDm | yes | 1352Stě0798472007 | m3 | Stěna | 0 | 0.125 | 16.47 | 16.47 | 2.059 | 5.4 | 2.059 | 0.675 | 3.05
ZDIVO Z CDm | Půdorys 1.PP | ZDIVO Z CDm 0.225 m | 1 | ZDIVO Z CDm | A | 1352HWa0798472036 | m3 | Celá stěna | Stávající | Zednické práce | ZDIVO Z CDm |  | 1352Stě0798472038 | m3 | Stěna | 0 | 0.225 | 1.906 | 1.906 | 0.429 | 0.625 | 0.429 | 0.141 | 3.05
ZDIVO Z CDm | Půdorys 1.PP | ZDIVO Z CDm 0.125 m | 1 | ZDIVO Z CDm | A | 1352HWa0798472086 | m3 | Celá stěna | Stávající | Zednické práce | ZDIVO Z CDm | yes | 1352Stě0798472087 | m3 | Stěna | 0 | 0.125 | 1.906 | 1.906 | 0.238 | 0.625 | 0.238 | 0.078 | 3.05
ZDIVO Z CDm | Půdorys 1.PP | ZDIVO Z CDm 0.125 m | 1 | ZDIVO Z CDm | A | 1352HWa0798472096 | m3 | Celá stěna | Stávající | Zednické práce | ZDIVO Z CDm | yes | 1352Stě0798472097 | m3 | Stěna | 0 | 0.125 | 1.906 | 1.906 | 0.238 | 0.625 | 0.238 | 0.078 | 3.05
PÓROBETONOVÉ ZDIVO | Půdorys 1.PP | PÓROBETONOVÉ ZDIVO 0.1 m | 1 | PÓROBETONOVÉ ZDIVO | EI 120 | 1352HWa0798472408 | m3 | Celá stěna | Stávající | Zednické práce | PÓROBETONOVÉ ZDIVO |  | 1352Stě0798472409 | m2 | Stěna | 1.111 | 0.1 | 17.232 | 12.58 | 1.723 | 5.65 | 1.258 | 0.565 | 3.05 | Pset_WallCommon - AcousticRating: 37 dB
ZDIVO Z CDm | Půdorys 1.PP | ZDIVO Z CDm 0.125 m | 1 | ZDIVO Z CDm | A | 1352HWa0798472502 | m3 | Celá stěna | Stávající | Zednické práce | ZDIVO Z CDm | yes | 1352Stě0798472503 | m3 | Stěna | 0 | 0.125 | 1.601 | 1.601 | 0.2 | 0.525 | 0.2 | 0.066 | 3.05
ZDIVO Z CDm | Půdorys 1.PP | ZDIVO Z CDm 0.125 m | 1 | ZDIVO Z CDm | A | 1352HWa0798441979 | m3 | Celá stěna | Stávající | Zednické práce | ZDIVO Z CDm | yes | 1352Stě0798441980 | m3 | Stěna | 0 | 0.125 | 18.986 | 18.986 | 2.373 | 6.225 | 2.328 | 0.778 | 3.05
PÓROBETONOVÉ ZDIVO | Půdorys 1.PP | PÓROBETONOVÉ ZDIVO 0.1 m | 1 | PÓROBETONOVÉ ZDIVO | EI 120 | 1352HWa0798442034 | m3 | Celá stěna | Stávající | Zednické práce | PÓROBETONOVÉ ZDIVO | no | 1352Stě0798442035 | m2 | Stěna | 1.111 | 0.1 | 8.54 | 8.54 | 0.854 | 2.8 | 0.854 | 0.28 | 3.05 | Pset_WallCommon - AcousticRating: 37 dB
ZDIVO Z CDm | Půdorys 1.PP | ZDIVO Z CDm 0.2 m | 1 | ZDIVO Z CDm | A | 1352HWa0798441988 | m3 | Celá stěna | Stávající | Zednické práce | ZDIVO Z CDm |  | 1352Stě0798441989 | m3 | Stěna | 0 | 0.2 | 1.83 | 1.83 | 0.366 | 0.6 | 0.366 | 0.12 | 3.05
ZDIVO Z CDm | Půdorys 1.PP | ZDIVO Z CDm 0.125 m | 1 | ZDIVO Z CDm | A | 1352HWa0798473306 | m3 | Celá stěna | Stávající | Zednické práce | ZDIVO Z CDm | yes | 1352Stě0798473308 | m3 | Stěna | 0 | 0.125 | 19.825 | 19.825 | 2.478 | 6.5 | 2.478 | 0.813 | 3.05
ZDIVO Z CDm | Půdorys 1.PP | ZDIVO Z CDm 0.125 m | 1 | ZDIVO Z CDm | A | 1352HWa0798473261 | m3 | Celá stěna | Stávající | Zednické práce | ZDIVO Z CDm | yes | 1352Stě0798473267 | m3 | Stěna | 0 | 0.125 | 7.244 | 7.244 | 0.905 | 2.375 | 0.905 | 0.297 | 3.05
ZDIVO Z CDm | Půdorys 1.PP | ZDIVO Z CDm 0.125 m | 1 | ZDIVO Z CDm | A | 1352HWa0798473262 | m3 | Celá stěna | Stávající | Zednické práce | ZDIVO Z CDm | yes | 1352Stě0798473269 | m3 | Stěna | 0 | 0.125 | 11.895 | 11.895 | 1.487 | 3.9 | 1.487 | 0.488 | 3.05
ZDIVO Z CDm | Půdorys 1.PP | ZDIVO Z CDm 0.125 m | 1 | ZDIVO Z CDm | A | 1352HWa0798473613 | m3 | Celá stěna | Stávající | Zednické práce | ZDIVO Z CDm | yes | 1352Stě0798473614 | m3 | Stěna | 0 | 0.125 | 1.677 | 1.678 | 0.21 | 0.55 | 0.21 | 0.069 | 3.05
ZDIVO Z CDm | Půdorys 1.PP | ZDIVO Z CDm 0.125 m | 1 | ZDIVO Z CDm | A | 1352HWa0798473618 | m3 | Celá stěna | Stávající | Zednické práce | ZDIVO Z CDm | yes | 1352Stě0798473619 | m3 | Stěna | 0 | 0.125 | 1.449 | 1.449 | 0.181 | 0.475 | 0.181 | 0.059 | 3.05
ZDIVO Z CDm | Půdorys 1.PP | ZDIVO Z CDm 0.125 m | 1 | ZDIVO Z CDm | A | 1352HWa0798473629 | m3 | Celá stěna | Stávající | Zednické práce | ZDIVO Z CDm | yes | 1352Stě0798473630 | m3 | Stěna | 0 | 0.125 | 1.296 | 1.296 | 0.162 | 0.425 | 0.162 | 0.053 | 3.05
ZDIVO Z CDm | Půdorys 1.PP | ZDIVO Z CDm 0.125 m | 1 | ZDIVO Z CDm | A | 1352HWa0000013124 | m3 | Celá stěna | Stávající | Zednické práce | ZDIVO Z CDm | yes | 1352Stě0000013128 | m3 | Stěna | 0 | 0.125 | 4.346 | 3.856 | 0.543 | 1.425 | 0.482 | 0.178 | 3.05
ZDIVO Z CDm | Půdorys 1.PP | ZDIVO Z CDm 0.125 m | 1 | ZDIVO Z CDm | A | 1352HWa0798474144 | m3 | Celá stěna | Stávající | Zednické práce | ZDIVO Z CDm | yes | 1352Stě0798474152 | m3 | Stěna | 0 | 0.125 | 13.725 | 11.147 | 1.716 | 4.5 | 1.393 | 0.563 | 3.05
PÓROBETONOVÉ ZDIVO | Půdorys 1.PP | PÓROBETONOVÉ ZDIVO 0.1 m | 1 | PÓROBETONOVÉ ZDIVO | EI 120 | 1352HWa0798459673 | m3 | Celá stěna | Stávající | Zednické práce | PÓROBETONOVÉ ZDIVO |  | 1352Stě0798459684 | m2 | Stěna | 1.111 | 0.1 | 11.743 | 9.943 | 1.174 | 3.85 | 0.994 | 0.385 | 3.05 | Pset_WallCommon - AcousticRating: 37 dB
ZELEZOBETONOVÁ KCE | Půdorys 1.PP | ZELEZOBETONOVÁ KCE 0.2 m, LIGNOPOR 0.025 m, PÓROBETONOVÉ ZDIVO 0.08 m | 1 | ZELEZOBETONOVÁ KCE | A | 1352HWa0798474694 | m3 | Celá stěna | Stávající | Betonářské práce | ZELEZOBETONOVÁ KCE |  | 1352Stě0798474708 | m3 | Stěna | 0 | 0.305 | 9.614 | 7.815 | 2.446 | 2.913 | 2.041 | 0.884 | 3.35 | NEMSOK - Object Layer Attributes #2, 2D interakce: yes; Object Layer Attributes #2, Status: Stávající; Object Layer Attributes #2, Práce: Zateplovací systémy; Object Layer Attributes #2, Materiál: LIGNOPOR; Object Layer Attributes #2, Allright_Stavebni_dil_ID: 1352Stě0798474709; Object Layer Attributes #2, Jednotka: m2; Object Layer Attributes #2, Název_objektu: Stěna; Object Layer Attributes #3, 2D interakce: yes; Object Layer Attributes #3, Status: Stávající; Object Layer Attributes #3, Práce: Zednické práce; Object Layer Attributes #3, Materiál: PÓROBETONOVÉ ZDIVO; Object Layer Attributes #3, Allright_Stavebni_dil_ID: 1352Stě0798474710; Object Layer Attributes #3, Jednotka: m2; Object Layer Attributes #3, Název_objektu: Stěna; Pset_WallCommon - LoadBearing: yes
PÓROBETONOVÉ ZDIVO | Půdorys 1.PP | PÓROBETONOVÉ ZDIVO 0.1 m | 1 | PÓROBETONOVÉ ZDIVO | EI 120 | 1352HWa0798443162 | m3 | Celá stěna | Stávající | Zednické práce | PÓROBETONOVÉ ZDIVO |  | 1352Stě0798443163 | m2 | Stěna | 1.111 | 0.1 | 0.671 | 0.671 | 0.067 | 0.22 | 0.067 | 0.022 | 3.05 | Pset_WallCommon - AcousticRating: 37 dB
ZELEZOBETONOVÁ KCE | Půdorys 1.PP | ZELEZOBETONOVÁ KCE 0.45 m, LIGNOPOR 0.025 m, PÓROBETONOVÉ ZDIVO 0.08 m | 1 | ZELEZOBETONOVÁ KCE | A | 1352HWa0798475932 | m3 | Celá stěna | Stávající | Betonářské práce | ZELEZOBETONOVÁ KCE |  | 1352Stě0798475935 | m3 | Stěna | 0 | 0.555 | 8.893 | 7.266 | 4.141 | 2.169 | 3.913 | 1.204 | 4.1 | NEMSOK - Object Layer Attributes #2, 2D interakce: yes; Object Layer Attributes #2, Status: Stávající; Object Layer Attributes #2, Práce: Zateplovací systémy; Object Layer Attributes #2, Materiál: LIGNOPOR; Object Layer Attributes #2, Allright_Stavebni_dil_ID: 1352Stě0798475934; Object Layer Attributes #2, Jednotka: m2; Object Layer Attributes #2, Název_objektu: Stěna; Object Layer Attributes #3, 2D interakce: yes; Object Layer Attributes #3, Status: Stávající; Object Layer Attributes #3, Práce: Zednické práce; Object Layer Attributes #3, Materiál: PÓROBETONOVÉ ZDIVO; Object Layer Attributes #3, Allright_Stavebni_dil_ID: 1352Stě0798475936; Object Layer Attributes #3, Jednotka: m2; Object Layer Attributes #3, Název_objektu: Stěna; Pset_WallCommon - LoadBearing: yes
ZELEZOBETONOVÁ KCE | Půdorys 1.PP | ZELEZOBETONOVÁ KCE 0.45 m, LIGNOPOR 0.025 m, PÓROBETONOVÉ ZDIVO 0.08 m |  | ZELEZOBETONOVÁ KCE | A | 1352HWa0798476016 | m3 | Celá stěna | Stávající | Betonářské práce | ZELEZOBETONOVÁ KCE |  | 1352Stě0798476020 | m3 | Stěna | 0 | 0.555 | 10.629 | 10.629 | 5.72 | 3.173 | 5.72 | 1.761 | 3.35 | NEMSOK - Object Layer Attributes #2, 2D interakce: yes; Object Layer Attributes #2, Status: Stávající; Object Layer Attributes #2, Práce: Zateplovací systémy; Object Layer Attributes #2, Materiál: LIGNOPOR; Object Layer Attributes #2, Allright_Stavebni_dil_ID: 1352Stě0798476019; Object Layer Attributes #2, Jednotka: m2; Object Layer Attributes #2, Název_objektu: Stěna; Object Layer Attributes #3, 2D interakce: yes; Object Layer Attributes #3, Status: Stávající; Object Layer Attributes #3, Práce: Zednické práce; Object Layer Attributes #3, Materiál: PÓROBETONOVÉ ZDIVO; Object Layer Attributes #3, Allright_Stavebni_dil_ID: 1352Stě0798476018; Object Layer Attributes #3, Jednotka: m2; Object Layer Attributes #3, Název_objektu: Stěna; Pset_WallCommon - LoadBearing: yes
ZELEZOBETONOVÁ KCE | Půdorys 1.PP | ZELEZOBETONOVÁ KCE | 1 | ZELEZOBETONOVÁ KCE | A | 1352HWa0000002522 | m3 | Celá stěna | Stávající | Betonářské práce | ZELEZOBETONOVÁ KCE |  | 1352Stě0000002523 | m3 | Stěna | 0 | 0.555 | 4.851 | 4.851 | 1.918 | 1.1 | 1.918 | 0.555 | 4.1 | NEMSOK - Object Layer Attributes #2, 2D interakce: yes; Object Layer Attributes #2, Status: Stávající; Object Layer Attributes #2, Práce: Zateplovací systémy; Object Layer Attributes #2, Materiál: LIGNOPOR; Object Layer Attributes #2, Allright_Stavebni_dil_ID: 1352Stě0000002524; Object Layer Attributes #2, Jednotka: m2; Object Layer Attributes #2, Název_objektu: Stěna; Object Layer Attributes #3, 2D interakce: yes; Object Layer Attributes #3, Status: Stávající; Object Layer Attributes #3, Práce: Zednické práce; Object Layer Attributes #3, Materiál: PÓROBETONOVÉ ZDIVO; Object Layer Attributes #3, Allright_Stavebni_dil_ID: 1352Stě0798432774; Object Layer Attributes #3, Jednotka: m2; Object Layer Attributes #3, Název_objektu: Stěna; Pset_WallCommon - LoadBearing: yes
PÓROBETONOVÉ ZDIVO | Půdorys 1.PP | PÓROBETONOVÉ ZDIVO 0.1 m | 1 | PÓROBETONOVÉ ZDIVO | EI 120 | 1352HWa0798466325 | m3 | Celá stěna | Stávající | Zednické práce | PÓROBETONOVÉ ZDIVO | yes | 1352Stě0798466326 | m2 | Stěna | 1.111 | 0.1 | 11.819 | 11.819 | 1.182 | 3.875 | 1.182 | 0.387 | 3.05 | Pset_WallCommon - AcousticRating: 37 dB
PÓROBETONOVÉ ZDIVO | Půdorys 1.PP | PÓROBETONOVÉ ZDIVO 0.1 m | 1 | PÓROBETONOVÉ ZDIVO | EI 120 | 1352HWa0798476965 | m3 | Celá stěna | Stávající | Zednické práce | PÓROBETONOVÉ ZDIVO | yes | 1352Stě0798476966 | m2 | Stěna | 1.111 | 0.1 | 0.762 | 0.763 | 0.076 | 0.25 | 0.076 | 0.025 | 3.05 | Pset_WallCommon - AcousticRating: 37 dB
PÓROBETONOVÉ ZDIVO | Půdorys 1.PP | PÓROBETONOVÉ ZDIVO 0.1 m |  | PÓROBETONOVÉ ZDIVO | EI 120 | 1352HWa0798476974 | m3 | Celá stěna | Stávající | Zednické práce | PÓROBETONOVÉ ZDIVO | yes | 1352Stě0798476975 | m2 | Stěna | 1.111 | 0.1 | 39.975 | 39.975 | 3.997 | 13.325 | 3.997 | 1.332 | 3 | Pset_WallCommon - AcousticRating: 37 dB
PÓROBETONOVÉ ZDIVO | Půdorys 1.PP | PÓROBETONOVÉ ZDIVO 0.1 m |  | PÓROBETONOVÉ ZDIVO | EI 120 | 1352HWa0798477307 | m3 | Celá stěna | Stávající | Zednické práce | PÓROBETONOVÉ ZDIVO | yes | 1352Stě0798477308 | m2 | Stěna | 1.111 | 0.1 | 10.5 | 10.5 | 1.05 | 3.5 | 1.05 | 0.35 | 3 | Pset_WallCommon - AcousticRating: 37 dB
DŘEVĚNÁ KCE | Půdorys 1.PP | DŘEVĚNÁ KCE 0.1 m |  | DŘEVĚNÁ KCE | A | 1352HWa0798460969 | m3 | Celá stěna | Stávající | Suché stavební práce | DŘEVĚNÁ KCE | yes | 1352Stě0798460970 | m3 | Stěna | 0 | 0.1 | 29.775 | 27.694 | 2.978 | 9.925 | 2.769 | 0.992 | 3
ZELEZOBETONOVÁ KCE | Půdorys 1.PP | ZELEZOBETONOVÁ KCE 0.3 m, LIGNOPOR 0.025 m, PÓROBETONOVÉ ZDIVO 0.08 m |  | ZELEZOBETONOVÁ KCE | A | 1352HWa0798461899 | m3 | Celá stěna | Stávající | Betonářské práce | ZELEZOBETONOVÁ KCE | no | 1352Stě0798461900 | m3 | Stěna | 0 | 0.405 | 8.25 | 8.25 | 3.263 | 2.498 | 3.263 | 1.071 | 3.3 | NEMSOK - Object Layer Attributes #2, 2D interakce: yes; Object Layer Attributes #2, Status: Stávající; Object Layer Attributes #2, Práce: Zateplovací systémy; Object Layer Attributes #2, Materiál: LIGNOPOR; Object Layer Attributes #2, Allright_Stavebni_dil_ID: 1352Stě0798461901; Object Layer Attributes #2, Jednotka: m2; Object Layer Attributes #2, Název_objektu: Stěna; Object Layer Attributes #3, 2D interakce: yes; Object Layer Attributes #3, Status: Stávající; Object Layer Attributes #3, Práce: Zednické práce; Object Layer Attributes #3, Materiál: PÓROBETONOVÉ ZDIVO; Object Layer Attributes #3, Allright_Stavebni_dil_ID: 1352Stě0798461902; Object Layer Attributes #3, Jednotka: m2; Object Layer Attributes #3, Název_objektu: Stěna; Object Layer Attributes #2, Staticky nosná konstrukce: no; Object Layer Attributes #3, Staticky nosná konstrukce: no; Pset_WallCommon - LoadBearing: yes
ZELEZOBETONOVÁ KCE | Půdorys 1.PP | ZELEZOBETONOVÁ KCE |  | ZELEZOBETONOVÁ KCE | A | 1352HWa0798460911 | m3 | Celá stěna | Stávající | Betonářské práce | ZELEZOBETONOVÁ KCE | no | 1352Stě0798460912 | m3 | Stěna | 0 | 0.405 | 10.956 | 10.922 | 4.091 | 3.332 | 4.081 | 1.34 | 3.3 | NEMSOK - Object Layer Attributes #2, 2D interakce: yes; Object Layer Attributes #2, Status: Stávající; Object Layer Attributes #2, Práce: Zateplovací systémy; Object Layer Attributes #2, Materiál: LIGNOPOR; Object Layer Attributes #2, Allright_Stavebni_dil_ID: 1352Stě0798461757; Object Layer Attributes #2, Jednotka: m2; Object Layer Attributes #2, Název_objektu: Stěna; Object Layer Attributes #3, 2D interakce: yes; Object Layer Attributes #3, Status: Stávající; Object Layer Attributes #3, Práce: Zednické práce; Object Layer Attributes #3, Materiál: PÓROBETONOVÉ ZDIVO; Object Layer Attributes #3, Allright_Stavebni_dil_ID: 1352Stě0798461758; Object Layer Attributes #3, Jednotka: m2; Object Layer Attributes #3, Název_objektu: Stěna; Object Layer Attributes #2, Staticky nosná konstrukce: no; Object Layer Attributes #3, Staticky nosná konstrukce: no; Pset_WallCommon - LoadBearing: yes
ZELEZOBETONOVÁ KCE | Půdorys 1.PP | ZELEZOBETONOVÁ KCE 0.2 m |  | ZELEZOBETONOVÁ KCE | A | 1352HWa0000005117 | m3 | Celá stěna | Stávající | Betonářské práce | ZELEZOBETONOVÁ KCE | yes | 1352Stě0000005120 | m3 | Stěna | 0 | 0.2 | 3.89 | 3.89 | 0.778 | 1.06 | 0.778 | 0.212 | 3.67
ZELEZOBETONOVÁ KCE | Půdorys 1.PP | ZELEZOBETONOVÁ KCE 0.2 m |  | ZELEZOBETONOVÁ KCE | A | 1352HWa0000005030 | m3 | Celá stěna | Stávající | Betonářské práce | ZELEZOBETONOVÁ KCE | yes | 1352Stě0000005031 | m3 | Stěna | 0 | 0.2 | 46.334 | 46.334 | 9.267 | 12.625 | 9.267 | 2.525 | 3.67
ZELEZOBETONOVÁ KCE | Půdorys 1.PP | ZELEZOBETONOVÁ KCE 0.15 m | 1 | ZELEZOBETONOVÁ KCE | A | 1352HWa0798480395 | m3 | Celá stěna | Stávající | Betonářské práce | ZELEZOBETONOVÁ KCE |  | 1352Stě0798480396 | m3 | Stěna | 0 | 0.15 | 1.25 | 1.25 | 0.187 | 1 | 0.187 | 0.15 | 1.25
ZELEZOBETONOVÁ KCE | Půdorys 1.PP | ZELEZOBETONOVÁ KCE 0.15 m | 1 | ZELEZOBETONOVÁ KCE | A | 1352HWa0798480400 | m3 | Celá stěna | Stávající | Betonářské práce | ZELEZOBETONOVÁ KCE |  | 1352Stě0798480401 | m3 | Stěna | 0 | 0.15 | 1.063 | 1.063 | 0.159 | 0.85 | 0.159 | 0.127 | 1.25
ZELEZOBETONOVÁ KCE | Půdorys 1.PP | ZELEZOBETONOVÁ KCE 0.15 m | 1 | ZELEZOBETONOVÁ KCE | A | 1352HWa0798480410 | m3 | Celá stěna | Stávající | Betonářské práce | ZELEZOBETONOVÁ KCE |  | 1352Stě0798480411 | m3 | Stěna | 0 | 0.15 | 1.063 | 1.063 | 0.159 | 0.85 | 0.159 | 0.127 | 1.25
ZELEZOBETONOVÁ KCE | Půdorys 1.PP | ZELEZOBETONOVÁ KCE 0.15 m | 1 | ZELEZOBETONOVÁ KCE | A | 1352HWa0798480422 | m3 | Celá stěna | Stávající | Betonářské práce | ZELEZOBETONOVÁ KCE |  | 1352Stě0798480423 | m3 | Stěna | 0 | 0.15 | 0.875 | 0.875 | 0.131 | 0.7 | 0.131 | 0.105 | 1.25
PÓROBETONOVÉ ZDIVO | Půdorys 1.PP | PÓROBETONOVÉ ZDIVO 0.1 m | 1 | PÓROBETONOVÉ ZDIVO | EI 120 | 1352HWa0798448621 | m3 | Celá stěna | Stávající | Zednické práce | PÓROBETONOVÉ ZDIVO |  | 1352Stě0798448622 | m2 | Stěna | 1.111 | 0.1 | 8.54 | 8.54 | 0.854 | 2.8 | 0.854 | 0.28 | 3.05 | Pset_WallCommon - AcousticRating: 37 dB
ZDIVO Z CDm | Půdorys 1.PP | ZDIVO Z CDm 0.25 m |  | ZDIVO Z CDm | REI 120 | 1352HWa0798443364 | m3 | Celá stěna | Stávající | Zednické práce | ZDIVO Z CDm | no | 1352Stě0798443387 | m3 | Stěna | 0.22 | 0.25 | 10.294 | 5.644 | 2.573 | 3.375 | 1.411 | 0.844 | 3.05 | Pset_WallCommon - AcousticRating: 47 dB
ZDIVO Z CDm | Půdorys 1.PP | ZDIVO Z CDm 0.25 m |  | ZDIVO Z CDm | REI 120 | 1352HWa0798453372 | m3 | Celá stěna | Stávající | Zednické práce | ZDIVO Z CDm | no | 1352Stě0798453508 | m3 | Stěna | 0.22 | 0.25 | 34.389 | 22.063 | 8.597 | 11.275 | 5.516 | 2.819 | 3.05 | Pset_WallCommon - AcousticRating: 47 dB
ZDIVO Z CDm | Půdorys 1.PP | ZDIVO Z CDm 0.125 m | 1 | ZDIVO Z CDm | A | 1352HWa0798494325 | m3 | Celá stěna | Stávající | Zednické práce | ZDIVO Z CDm | yes | 1352Stě0798494334 | m3 | Stěna | 0 | 0.125 | 1.83 | 1.74 | 0.229 | 0.6 | 0.217 | 0.075 | 3.05
ZDIVO Z CDm | Půdorys 1.PP | ZDIVO Z CDm 0.125 m | 1 | ZDIVO Z CDm | A | 1352HWa0798494326 | m3 | Celá stěna | Stávající | Zednické práce | ZDIVO Z CDm | yes | 1352Stě0798494333 | m3 | Stěna | 0 | 0.125 | 1.22 | 1.22 | 0.152 | 0.4 | 0.152 | 0.05 | 3.05
ZDIVO Z CDm | Půdorys 1.PP | ZDIVO Z CDm 0.125 m | 1 | ZDIVO Z CDm | A | 1352HWa0798494404 | m3 | Celá stěna | Stávající | Zednické práce | ZDIVO Z CDm | yes | 1352Stě0798494405 | m3 | Stěna | 0 | 0.125 | 1.22 | 1.22 | 0.152 | 0.4 | 0.152 | 0.05 | 3.05
PREFA ŽB ENERGOKANÁL | Půdorys 1.PP | PREFA ŽB ENERGOKANÁL 0.1 m |  | PREFA ŽB ENERGOKANÁL | A | 1352HWa0798467412 | m3 | Celá stěna | Stávající | Betonářské práce | PREFA ŽB ENERGOKANÁL | yes | 1352Stě0798467414 | m3 | Stěna | 0 | 0.1 | 5.348 | 5.348 | 0.535 | 8.913 | 0.535 | 0.891 | 0.6
PREFA ŽB ENERGOKANÁL | Půdorys 1.PP | PREFA ŽB ENERGOKANÁL 0.1 m |  | PREFA ŽB ENERGOKANÁL | A | 1352HWa0798467399 | m3 | Celá stěna | Stávající | Betonářské práce | PREFA ŽB ENERGOKANÁL | yes | 1352Stě0798467401 | m3 | Stěna | 0 | 0.1 | 5.348 | 5.348 | 0.535 | 8.913 | 0.535 | 0.891 | 0.6
PREFA ŽB ENERGOKANÁL | Půdorys 1.PP | PREFA ŽB ENERGOKANÁL 0.1 m |  | PREFA ŽB ENERGOKANÁL | A | 1352HWa0798467327 | m3 | Celá stěna | Stávající | Betonářské práce | PREFA ŽB ENERGOKANÁL | yes | 1352Stě0798467328 | m3 | Stěna | 0 | 0.1 | 5.348 | 5.348 | 0.535 | 8.913 | 0.535 | 0.891 | 0.6
PREFA ŽB ENERGOKANÁL | Půdorys 1.PP | PREFA ŽB ENERGOKANÁL 0.1 m |  | PREFA ŽB ENERGOKANÁL | A | 1352HWa0798467344 | m3 | Celá stěna | Stávající | Betonářské práce | PREFA ŽB ENERGOKANÁL | yes | 1352Stě0798467346 | m3 | Stěna | 0 | 0.1 | 5.348 | 5.348 | 0.535 | 8.913 | 0.535 | 0.891 | 0.6
ZDIVO Z CDm | Půdorys 1.PP | ZDIVO Z CDm 0.125 m | 1 | ZDIVO Z CDm | A | 1352HWa0798459723 | m3 | Celá stěna | Stávající | Zednické práce | ZDIVO Z CDm | yes | 1352Stě0798459724 | m3 | Stěna | 0 | 0.125 | 24.476 | 20.201 | 3.06 | 8.025 | 2.525 | 1.003 | 3.05
ZELEZOBETONOVÁ KCE | Půdorys 1.PP | ZELEZOBETONOVÁ KCE 0.2 m, LIGNOPOR 0.025 m, PÓROBETONOVÉ ZDIVO 0.08 m |  | ZELEZOBETONOVÁ KCE | A | 1352HWa0798430625 | m3 | Celá stěna | Stávající | Betonářské práce | ZELEZOBETONOVÁ KCE |  | 1352Stě0798430641 | m3 | Stěna | 0 | 0.305 | 16.75 | 10.593 | 4.239 | 5 | 2.572 | 1.525 | 3.35 | NEMSOK - Object Layer Attributes #2, 2D interakce: yes; Object Layer Attributes #2, Status: Stávající; Object Layer Attributes #2, Práce: Zateplovací systémy; Object Layer Attributes #2, Materiál: LIGNOPOR; Object Layer Attributes #2, Allright_Stavebni_dil_ID: 1352Stě0798430640; Object Layer Attributes #2, Jednotka: m2; Object Layer Attributes #2, Název_objektu: Stěna; Object Layer Attributes #3, 2D interakce: yes; Object Layer Attributes #3, Status: Stávající; Object Layer Attributes #3, Práce: Zednické práce; Object Layer Attributes #3, Materiál: PÓROBETONOVÉ ZDIVO; Object Layer Attributes #3, Allright_Stavebni_dil_ID: 1352Stě0798430639; Object Layer Attributes #3, Jednotka: m2; Object Layer Attributes #3, Název_objektu: Stěna; Pset_WallCommon - LoadBearing: yes
ZELEZOBETONOVÁ KCE | Půdorys 1.PP | ZELEZOBETONOVÁ KCE | 1 | ZELEZOBETONOVÁ KCE | A | 1352HWa0000004000 | m3 | Celá stěna | Stávající | Betonářské práce | ZELEZOBETONOVÁ KCE |  | 1352Stě0000004001 | m3 | Stěna | 0 | 0.305 | 21.525 | 15.735 | 5.627 | 5.25 | 4.158 | 1.601 | 4.1 | NEMSOK - Object Layer Attributes #2, 2D interakce: yes; Object Layer Attributes #2, Status: Stávající; Object Layer Attributes #2, Práce: Zateplovací systémy; Object Layer Attributes #2, Materiál: LIGNOPOR; Object Layer Attributes #2, Allright_Stavebni_dil_ID: 1352Stě0000004002; Object Layer Attributes #2, Jednotka: m2; Object Layer Attributes #2, Název_objektu: Stěna; Object Layer Attributes #3, 2D interakce: yes; Object Layer Attributes #3, Status: Stávající; Object Layer Attributes #3, Práce: Zednické práce; Object Layer Attributes #3, Materiál: PÓROBETONOVÉ ZDIVO; Object Layer Attributes #3, Allright_Stavebni_dil_ID: 1352Stě0798433577; Object Layer Attributes #3, Jednotka: m2; Object Layer Attributes #3, Název_objektu: Stěna; Pset_WallCommon - LoadBearing: yes
ZDIVO Z CDm | Půdorys 1.PP | ZDIVO Z CDm 0.125 m | 1 | ZDIVO Z CDm | A | 1352HWa0798496256 | m3 | Celá stěna | Stávající | Zednické práce | ZDIVO Z CDm |  | 1352Stě0798496257 | m3 | Stěna | 0 | 0.125 | 12.779 | 12.78 | 1.597 | 4.19 | 1.597 | 0.524 | 3.05
ZDIVO Z CDm | Půdorys 1.PP | ZDIVO Z CDm 0.125 m | 1 | ZDIVO Z CDm | A | 1352HWa0798496271 | m3 | Celá stěna | Stávající | Zednické práce | ZDIVO Z CDm |  | 1352Stě0798496272 | m3 | Stěna | 0 | 0.125 | 3.553 | 3.553 | 0.444 | 1.165 | 0.444 | 0.146 | 3.05
ZDIVO Z CDm | Půdorys 1.PP | ZDIVO Z CDm 0.125 m | 1 | ZDIVO Z CDm | A | 1352HWa0798496278 | m3 | Celá stěna | Stávající | Zednické práce | ZDIVO Z CDm | yes | 1352Stě0798496279 | m3 | Stěna | 0 | 0.125 | 2.287 | 2.288 | 0.286 | 0.75 | 0.286 | 0.094 | 3.05
ZDIVO Z CDm | Půdorys 1.PP | ZDIVO Z CDm 0.125 m | 1 | ZDIVO Z CDm | A | 1352HWa0798496335 | m3 | Celá stěna | Stávající | Zednické práce | ZDIVO Z CDm | yes | 1352Stě0798496336 | m3 | Stěna | 0 | 0.125 | 5.795 | 5.795 | 0.724 | 1.9 | 0.724 | 0.237 | 3.05
ZDIVO Z CDm | Půdorys 1.PP | ZDIVO Z CDm 0.125 m | 1 | ZDIVO Z CDm | A | 1352HWa0798496340 | m3 | Celá stěna | Stávající | Zednické práce | ZDIVO Z CDm | yes | 1352Stě0798496341 | m3 | Stěna | 0 | 0.125 | 1.982 | 1.983 | 0.248 | 0.65 | 0.248 | 0.081 | 3.05
ZDIVO Z CDm | Půdorys 1.PP | ZDIVO Z CDm 0.125 m | 1 | ZDIVO Z CDm | A | 1352HWa0798496400 | m3 | Celá stěna | Stávající | Zednické práce | ZDIVO Z CDm | yes | 1352Stě0798496401 | m3 | Stěna | 0 | 0.125 | 3.431 | 3.431 | 0.429 | 1.125 | 0.429 | 0.141 | 3.05
ZDIVO Z CDm | Půdorys 1.PP | ZDIVO Z CDm 0.125 m | 1 | ZDIVO Z CDm | A | 1352HWa0798496410 | m3 | Celá stěna | Stávající | Zednické práce | ZDIVO Z CDm | yes | 1352Stě0798496411 | m3 | Stěna | 0 | 0.125 | 1.982 | 1.983 | 0.248 | 0.65 | 0.248 | 0.081 | 3.05
ZDIVO Z CDm | Půdorys 1.PP | ZDIVO Z CDm 0.125 m | 1 | ZDIVO Z CDm | A | 1352HWa0798496428 | m3 | Celá stěna | Stávající | Zednické práce | ZDIVO Z CDm | yes | 1352Stě0798496429 | m3 | Stěna | 0 | 0.125 | 8.86 | 6.739 | 1.108 | 2.905 | 0.842 | 0.363 | 3.05
ZDIVO Z CDm | Půdorys 1.PP | ZDIVO Z CDm 0.125 m | 1 | ZDIVO Z CDm | A | 1352HWa0798496445 | m3 | Celá stěna | Stávající | Zednické práce | ZDIVO Z CDm | yes | 1352Stě0798496446 | m3 | Stěna | 0 | 0.125 | 1.372 | 1.373 | 0.172 | 0.45 | 0.172 | 0.056 | 3.05
ZDIVO Z CDm | Půdorys 1.PP | ZDIVO Z CDm 0.125 m | 1 | ZDIVO Z CDm | A | 1352HWa0798496517 | m3 | Celá stěna | Stávající | Zednické práce | ZDIVO Z CDm | yes | 1352Stě0798496518 | m3 | Stěna | 0 | 0.125 | 0.839 | 0.839 | 0.105 | 0.275 | 0.105 | 0.034 | 3.05
ZDIVO Z CDm | Půdorys 1.PP | ZDIVO Z CDm 0.125 m | 1 | ZDIVO Z CDm | A | 1352HWa0798496530 | m3 | Celá stěna | Stávající | Zednické práce | ZDIVO Z CDm | yes | 1352Stě0798496531 | m3 | Stěna | 0 | 0.125 | 1.525 | 1.525 | 0.191 | 0.5 | 0.114 | 0.062 | 3.05
ZDIVO Z CDm | Půdorys 1.PP | ZDIVO Z CDm 0.125 m | 1 | ZDIVO Z CDm | A | 1352HWa0798496597 | m3 | Celá stěna | Stávající | Zednické práce | ZDIVO Z CDm | yes | 1352Stě0798496598 | m3 | Stěna | 0 | 0.125 | 13.039 | 13.039 | 1.63 | 4.275 | 1.63 | 0.534 | 3.05
ZDIVO Z CDm | Půdorys 1.PP | ZDIVO Z CDm 0.125 m | 1 | ZDIVO Z CDm | A | 1352HWa0798496266 | m3 | Celá stěna | Stávající | Zednické práce | ZDIVO Z CDm |  | 1352Stě0798496267 | m3 | Stěna | 0 | 0.125 | 12.779 | 12.78 | 1.597 | 4.19 | 1.597 | 0.524 | 3.05
ZDIVO Z CDm | Půdorys 1.PP | ZDIVO Z CDm 0.125 m | 1 | ZDIVO Z CDm | A | 1352HWa0798496780 | m3 | Celá stěna | Stávající | Zednické práce | ZDIVO Z CDm |  | 1352Stě0798496781 | m3 | Stěna | 0 | 0.125 | 1.342 | 1.342 | 0.168 | 0.44 | 0.168 | 0.055 | 3.05
ZDIVO Z CDm | Půdorys 1.PP | ZDIVO Z CDm 0.125 m | 1 | ZDIVO Z CDm | A | 1352HWa0798496790 | m3 | Celá stěna | Stávající | Zednické práce | ZDIVO Z CDm | yes | 1352Stě0798496791 | m3 | Stěna | 0 | 0.125 | 2.135 | 2.135 | 0.267 | 0.7 | 0.267 | 0.087 | 3.05
ZDIVO Z CDm | Půdorys 1.PP | ZDIVO Z CDm 0.125 m | 1 | ZDIVO Z CDm | A | 1352HWa0798496800 | m3 | Celá stěna | Stávající | Zednické práce | ZDIVO Z CDm | yes | 1352Stě0798496801 | m3 | Stěna | 0 | 0.125 | 1.327 | 1.327 | 0.166 | 0.435 | 0.166 | 0.054 | 3.05
ZDIVO Z CDm | Půdorys 1.PP | ZDIVO Z CDm 0.125 m | 1 | ZDIVO Z CDm | A | 1352HWa0798496883 | m3 | Celá stěna | Stávající | Zednické práce | ZDIVO Z CDm | yes | 1352Stě0798496884 | m3 | Stěna | 0 | 0.125 | 3.317 | 2.012 | 0.415 | 1.088 | 0.251 | 0.136 | 3.05
ZDIVO Z CDm | Půdorys 1.PP | ZDIVO Z CDm 0.125 m | 1 | ZDIVO Z CDm | A | 1352HWa0798496932 | m3 | Celá stěna | Stávající | Zednické práce | ZDIVO Z CDm | yes | 1352Stě0798496933 | m3 | Stěna | 0 | 0.125 | 4.727 | 3.314 | 0.591 | 1.55 | 0.414 | 0.194 | 3.05
ZDIVO Z CDm | Půdorys 1.PP | ZDIVO Z CDm 0.125 m | 1 | ZDIVO Z CDm | A | 1352HWa0798496947 | m3 | Celá stěna | Stávající | Zednické práce | ZDIVO Z CDm | yes | 1352Stě0798496948 | m3 | Stěna | 0 | 0.125 | 4.727 | 4.728 | 0.591 | 1.55 | 0.591 | 0.194 | 3.05
ZDIVO Z CDm | Půdorys 1.PP | ZDIVO Z CDm 0.125 m | 1 | ZDIVO Z CDm | A | 1352HWa0798496962 | m3 | Celá stěna | Stávající | Zednické práce | ZDIVO Z CDm | yes | 1352Stě0798496963 | m3 | Stěna | 0 | 0.125 | 4.727 | 3.516 | 0.591 | 1.55 | 0.439 | 0.194 | 3.05
ZDIVO Z CDm | Půdorys 1.PP | ZDIVO Z CDm 0.125 m | 1 | ZDIVO Z CDm | A | 1352HWa0798497072 | m3 | Celá stěna | Stávající | Zednické práce | ZDIVO Z CDm | yes | 1352Stě0798497073 | m3 | Stěna | 0 | 0.125 | 7.716 | 7.717 | 0.965 | 2.53 | 0.965 | 0.316 | 3.05
ZDIVO Z CDm | Půdorys 1.PP | ZDIVO Z CDm 0.125 m | 1 | ZDIVO Z CDm | A | 1352HWa0798497082 | m3 | Celá stěna | Stávající | Zednické práce | ZDIVO Z CDm | yes | 1352Stě0798497083 | m3 | Stěna | 0 | 0.125 | 2.592 | 2.593 | 0.324 | 0.85 | 0.324 | 0.106 | 3.05
ZDIVO Z CDm | Půdorys 1.PP | ZDIVO Z CDm 0.125 m | 1 | ZDIVO Z CDm | A | 1352HWa0798497092 | m3 | Celá stěna | Stávající | Zednické práce | ZDIVO Z CDm | yes | 1352Stě0798497093 | m3 | Stěna | 0 | 0.125 | 3.126 | 2.466 | 0.391 | 1.025 | 0.308 | 0.128 | 3.05
ZDIVO Z CDm | Půdorys 1.PP | ZDIVO Z CDm 0.125 m | 1 | ZDIVO Z CDm | A | 1352HWa0798497160 | m3 | Celá stěna | Stávající | Zednické práce | ZDIVO Z CDm | yes | 1352Stě0798497161 | m3 | Stěna | 0 | 0.125 | 38.75 | 27.591 | 4.844 | 12.705 | 3.449 | 1.588 | 3.05
ZDIVO Z CDm | Půdorys 1.PP | ZDIVO Z CDm 0.125 m | 1 | ZDIVO Z CDm | A | 1352HWa0798497226 | m3 | Celá stěna | Stávající | Zednické práce | ZDIVO Z CDm | yes | 1352Stě0798497227 | m3 | Stěna | 0 | 0.125 | 17.477 | 15.053 | 2.185 | 5.73 | 1.882 | 0.716 | 3.05
ZDIVO Z CDm | Půdorys 1.PP | ZDIVO Z CDm | 1 | ZDIVO Z CDm | A | 1352HWa0798497176 | m3 | Celá stěna | Stávající | Zednické práce | ZDIVO Z CDm | yes | 1352Stě0798497177 | m3 | Stěna | 0 | 0.125 | 20.603 | 20.603 | 2.575 | 6.755 | 2.575 | 0.844 | 3.05
ZDIVO Z CDm | Půdorys 1.PP | ZDIVO Z CDm 0.125 m | 1 | ZDIVO Z CDm | A | 1352HWa0798497245 | m3 | Celá stěna | Stávající | Zednické práce | ZDIVO Z CDm | yes | 1352Stě0798497246 | m3 | Stěna | 0 | 0.125 | 2.089 | 2.089 | 0.261 | 0.685 | 0.261 | 0.086 | 3.05
ZDIVO Z CDm | Půdorys 1.PP | ZDIVO Z CDm 0.125 m | 1 | ZDIVO Z CDm | A | 1352HWa0798497255 | m3 | Celá stěna | Stávající | Zednické práce | ZDIVO Z CDm | yes | 1352Stě0798497256 | m3 | Stěna | 0 | 0.125 | 2.089 | 2.089 | 0.261 | 0.685 | 0.261 | 0.086 | 3.05
ZDIVO Z CDm | Půdorys 1.PP | ZDIVO Z CDm 0.125 m | 1 | ZDIVO Z CDm | A | 1352HWa0798497265 | m3 | Celá stěna | Stávající | Zednické práce | ZDIVO Z CDm | yes | 1352Stě0798497266 | m3 | Stěna | 0 | 0.125 | 2.089 | 2.089 | 0.261 | 0.685 | 0.261 | 0.086 | 3.05
ZDIVO Z CDm | Půdorys 1.PP | ZDIVO Z CDm 0.125 m | 1 | ZDIVO Z CDm | A | 1352HWa0798497275 | m3 | Celá stěna | Stávající | Zednické práce | ZDIVO Z CDm | yes | 1352Stě0798497276 | m3 | Stěna | 0 | 0.125 | 6.893 | 6.893 | 0.862 | 2.26 | 0.862 | 0.282 | 3.05
ZDIVO Z CDm | Půdorys 1.PP | ZDIVO Z CDm 0.125 m | 1 | ZDIVO Z CDm | A | 1352HWa0798497285 | m3 | Celá stěna | Stávající | Zednické práce | ZDIVO Z CDm | yes | 1352Stě0798497286 | m3 | Stěna | 0 | 0.125 | 2.211 | 2.211 | 0.276 | 0.725 | 0.276 | 0.091 | 3.05
ZDIVO Z CDm | Půdorys 1.PP | ZDIVO Z CDm 0.125 m | 1 | ZDIVO Z CDm | A | 1352HWa0798497295 | m3 | Celá stěna | Stávající | Zednické práce | ZDIVO Z CDm | yes | 1352Stě0798497296 | m3 | Stěna | 0 | 0.125 | 13.71 | 11.892 | 1.714 | 4.495 | 1.486 | 0.562 | 3.05
ZDIVO Z CDm | Půdorys 1.PP | ZDIVO Z CDm 0.125 m |  | ZDIVO Z CDm | A | 1352HWa0798450398 | m3 | Celá stěna | Stávající | Zednické práce | ZDIVO Z CDm | yes | 1352Stě0798450399 | m3 | Stěna | 0 | 0.125 | 1.8 | 1.8 | 0.225 | 0.75 | 0.225 | 0.094 | 2.4
ZDIVO Z CDm | Půdorys 1.PP | ZDIVO Z CDm 0.125 m |  | ZDIVO Z CDm | A | 1352HWa0798450408 | m3 | Celá stěna | Stávající | Zednické práce | ZDIVO Z CDm | yes | 1352Stě0798450409 | m3 | Stěna | 0 | 0.125 | 3.72 | 3.72 | 0.465 | 1.55 | 0.465 | 0.194 | 2.4
ZDIVO Z CDm | Půdorys 1.PP | ZDIVO Z CDm 0.125 m | 1 | ZDIVO Z CDm | A | 1352HWa0798497312 | m3 | Celá stěna | Stávající | Zednické práce | ZDIVO Z CDm | yes | 1352Stě0798497313 | m3 | Stěna | 0 | 0.125 | 2.592 | 2.593 | 0.324 | 0.85 | 0.324 | 0.106 | 3.05
ZDIVO Z CDm | Půdorys 1.PP | ZDIVO Z CDm 0.125 m | 1 | ZDIVO Z CDm | A | 1352HWa0798497614 | m3 | Celá stěna | Stávající | Zednické práce | ZDIVO Z CDm | yes | 1352Stě0798497615 | m3 | Stěna | 0 | 0.125 | 4.59 | 3.87 | 0.574 | 1.505 | 0.484 | 0.188 | 3.05
ZDIVO Z CDm | Půdorys 1.PP | ZDIVO Z CDm 0.125 m | 1 | ZDIVO Z CDm | A | 1352HWa0798497624 | m3 | Celá stěna | Stávající | Zednické práce | ZDIVO Z CDm | yes | 1352Stě0798497625 | m3 | Stěna | 0 | 0.125 | 4.59 | 4.59 | 0.574 | 1.505 | 0.574 | 0.188 | 3.05
PÓROBETONOVÉ ZDIVO | Půdorys 1.PP | PÓROBETONOVÉ ZDIVO 0.1 m | 1 | PÓROBETONOVÉ ZDIVO | EI 120 | 1352HWa0798500089 | m3 | Celá stěna | Stávající | Zednické práce | PÓROBETONOVÉ ZDIVO |  | 1352Stě0798500090 | m2 | Stěna | 1.111 | 0.1 | 9.76 | 9.76 | 0.976 | 3.2 | 0.976 | 0.32 | 3.05 | Pset_WallCommon - AcousticRating: 37 dB
PÓROBETONOVÉ ZDIVO | Půdorys 1.PP | PÓROBETONOVÉ ZDIVO 0.1 m | 1 | PÓROBETONOVÉ ZDIVO | EI 120 | 1352HWa0798500100 | m3 | Celá stěna | Stávající | Zednické práce | PÓROBETONOVÉ ZDIVO |  | 1352Stě0798500101 | m2 | Stěna | 1.111 | 0.1 | 9.76 | 9.76 | 0.976 | 3.2 | 0.976 | 0.32 | 3.05 | Pset_WallCommon - AcousticRating: 37 dB
ZDIVO Z CDm | Půdorys 1.PP | ZDIVO Z CDm 0.125 m | 1 | ZDIVO Z CDm | A | 1352HWa0798500110 | m3 | Celá stěna | Stávající | Zednické práce | ZDIVO Z CDm | yes | 1352Stě0798500129 | m3 | Stěna | 0 | 0.125 | 16.775 | 14.656 | 2.097 | 5.5 | 1.794 | 0.687 | 3.05
PÓROBETONOVÉ ZDIVO | Půdorys 1.PP | PÓROBETONOVÉ ZDIVO 0.1 m | 1 | PÓROBETONOVÉ ZDIVO | EI 120 | 1352HWa0798500196 | m3 | Celá stěna | Stávající | Zednické práce | PÓROBETONOVÉ ZDIVO |  | 1352Stě0798500197 | m2 | Stěna | 1.111 | 0.1 | 9.15 | 9.15 | 0.915 | 3 | 0.915 | 0.3 | 3.05 | Pset_WallCommon - AcousticRating: 37 dB
PÓROBETONOVÉ ZDIVO | Půdorys 1.PP | PÓROBETONOVÉ ZDIVO 0.1 m | 1 | PÓROBETONOVÉ ZDIVO | EI 120 | 1352HWa0798500202 | m3 | Celá stěna | Stávající | Zednické práce | PÓROBETONOVÉ ZDIVO |  | 1352Stě0798500203 | m2 | Stěna | 1.111 | 0.1 | 15.555 | 15.555 | 1.556 | 5.1 | 1.556 | 0.51 | 3.05 | Pset_WallCommon - AcousticRating: 37 dB
PÓROBETONOVÉ ZDIVO | Půdorys 1.PP | PÓROBETONOVÉ ZDIVO 0.1 m | 1 | PÓROBETONOVÉ ZDIVO | EI 120 | 1352HWa0798500208 | m3 | Celá stěna | Stávající | Zednické práce | PÓROBETONOVÉ ZDIVO |  | 1352Stě0798500209 | m2 | Stěna | 1.111 | 0.1 | 0.458 | 0.458 | 0.046 | 0.15 | 0.046 | 0.015 | 3.05 | Pset_WallCommon - AcousticRating: 37 dB
ZDIVO Z CDm | Půdorys 1.PP | ZDIVO Z CDm 0.125 m | 1 | ZDIVO Z CDm | A | 1352HWa0798500238 | m3 | Celá stěna | Stávající | Zednické práce | ZDIVO Z CDm | yes | 1352Stě0798500239 | m3 | Stěna | 0 | 0.125 | 2.394 | 2.394 | 0.299 | 0.785 | 0.299 | 0.098 | 3.05
PÓROBETONOVÉ ZDIVO | Půdorys 1.PP | PÓROBETONOVÉ ZDIVO 0.1 m | 1 | PÓROBETONOVÉ ZDIVO | EI 120 | 1352HWa0798500274 | m3 | Celá stěna | Stávající | Zednické práce | PÓROBETONOVÉ ZDIVO |  | 1352Stě0798500275 | m2 | Stěna | 1.111 | 0.1 | 0.153 | 0.153 | 0.015 | 0.05 | 0.015 | 0.005 | 3.05 | Pset_WallCommon - AcousticRating: 37 dB
PÓROBETONOVÉ ZDIVO | Půdorys 1.PP | PÓROBETONOVÉ ZDIVO 0.1 m | 1 | PÓROBETONOVÉ ZDIVO | EI 120 | 1352HWa0798500294 | m3 | Celá stěna | Stávající | Zednické práce | PÓROBETONOVÉ ZDIVO |  | 1352Stě0798500296 | m2 | Stěna | 1.111 | 0.1 | 15.86 | 15.86 | 1.586 | 5.2 | 1.586 | 0.52 | 3.05 | Pset_WallCommon - AcousticRating: 37 dB
ZDIVO Z CDm | Půdorys 1.PP | ZDIVO Z CDm 0.125 m | 1 | ZDIVO Z CDm | A | 1352HWa0798500343 | m3 | Celá stěna | Stávající | Zednické práce | ZDIVO Z CDm |  | 1352Stě0798500344 | m3 | Stěna | 0 | 0.125 | 1.465 | 1.465 | 0.183 | 0.5 | 0.183 | 0.063 | 2.93
ZDIVO Z CDm | Půdorys 1.PP | ZDIVO Z CDm 0.125 m | 1 | ZDIVO Z CDm | A | 1352HWa0798500321 | m3 | Celá stěna | Stávající | Zednické práce | ZDIVO Z CDm |  | 1352Stě0798500322 | m3 | Stěna | 0 | 0.125 | 1.465 | 1.465 | 0.183 | 0.5 | 0.183 | 0.063 | 2.93
ZELEZOBETONOVÁ KCE | Půdorys 1.PP | ZELEZOBETONOVÁ KCE 0.45 m, LIGNOPOR 0.025 m, PÓROBETONOVÉ ZDIVO 0.08 m |  | ZELEZOBETONOVÁ KCE | A | 1352HWa0000001889 | m3 | Celá stěna | Stávající | Betonářské práce | ZELEZOBETONOVÁ KCE |  | 1352Stě0000001890 | m3 | Stěna | 0 | 0.555 | 15.092 | 15.092 | 5.542 | 3.202 | 5.542 | 1.64 | 4.4 | NEMSOK - Object Layer Attributes #2, 2D interakce: yes; Object Layer Attributes #2, Status: Stávající; Object Layer Attributes #2, Práce: Zateplovací systémy; Object Layer Attributes #2, Materiál: LIGNOPOR; Object Layer Attributes #2, Allright_Stavebni_dil_ID: 1352Stě0000002093; Object Layer Attributes #2, Jednotka: m2; Object Layer Attributes #2, Název_objektu: Stěna; Object Layer Attributes #3, 2D interakce: yes; Object Layer Attributes #3, Status: Stávající; Object Layer Attributes #3, Práce: Zednické práce; Object Layer Attributes #3, Materiál: PÓROBETONOVÉ ZDIVO; Object Layer Attributes #3, Allright_Stavebni_dil_ID: 1352Stě0798433894; Object Layer Attributes #3, Jednotka: m2; Object Layer Attributes #3, Název_objektu: Stěna; Pset_WallCommon - LoadBearing: yes
ZDIVO Z CDm | Půdorys 1.PP | ZDIVO Z CDm 0.125 m | 1 | ZDIVO Z CDm | A | 1352HWa0798500365 | m3 | Celá stěna | Stávající | Zednické práce | ZDIVO Z CDm |  | 1352Stě0798500367 | m3 | Stěna | 0 | 0.125 | 4.981 | 4.981 | 0.623 | 1.7 | 0.623 | 0.212 | 2.93
ZELEZOBETONOVÁ KCE | Půdorys 1.PP | ZELEZOBETONOVÁ KCE 0.2 m, LIGNOPOR 0.025 m, PÓROBETONOVÉ ZDIVO 0.08 m |  | ZELEZOBETONOVÁ KCE | A | 1352HWa0000003946 | m3 | Celá stěna | Stávající | Betonářské práce | ZELEZOBETONOVÁ KCE |  | 1352Stě0000003947 | m3 | Stěna | 0 | 0.305 | 42.21 | 36.81 | 10.883 | 12.775 | 9.668 | 3.871 | 3.35 | NEMSOK - Object Layer Attributes #2, 2D interakce: yes; Object Layer Attributes #2, Status: Stávající; Object Layer Attributes #2, Práce: Zateplovací systémy; Object Layer Attributes #2, Materiál: LIGNOPOR; Object Layer Attributes #2, Allright_Stavebni_dil_ID: 1352Stě0000003948; Object Layer Attributes #2, Jednotka: m2; Object Layer Attributes #2, Název_objektu: Stěna; Object Layer Attributes #3, 2D interakce: yes; Object Layer Attributes #3, Status: Stávající; Object Layer Attributes #3, Práce: Zednické práce; Object Layer Attributes #3, Materiál: PÓROBETONOVÉ ZDIVO; Object Layer Attributes #3, Allright_Stavebni_dil_ID: 1352Stě0798432693; Object Layer Attributes #3, Jednotka: m2; Object Layer Attributes #3, Název_objektu: Stěna; Pset_WallCommon - LoadBearing: yes
ZELEZOBETONOVÁ KCE | Půdorys 1.PP | ZELEZOBETONOVÁ KCE 0.2 m, LIGNOPOR 0.025 m, PÓROBETONOVÉ ZDIVO 0.08 m |  | ZELEZOBETONOVÁ KCE | A | 1352HWa0798430547 | m3 | Celá stěna | Stávající | Betonářské práce | ZELEZOBETONOVÁ KCE |  | 1352Stě0798430564 | m3 | Stěna | 0 | 0.305 | 25.025 | 24.935 | 5.891 | 7.513 | 5.871 | 2.287 | 3.35 | NEMSOK - Object Layer Attributes #2, 2D interakce: yes; Object Layer Attributes #2, Status: Stávající; Object Layer Attributes #2, Práce: Zateplovací systémy; Object Layer Attributes #2, Materiál: LIGNOPOR; Object Layer Attributes #2, Allright_Stavebni_dil_ID: 1352Stě0798430565; Object Layer Attributes #2, Jednotka: m2; Object Layer Attributes #2, Název_objektu: Stěna; Object Layer Attributes #3, 2D interakce: yes; Object Layer Attributes #3, Status: Stávající; Object Layer Attributes #3, Práce: Zednické práce; Object Layer Attributes #3, Materiál: PÓROBETONOVÉ ZDIVO; Object Layer Attributes #3, Allright_Stavebni_dil_ID: 1352Stě0798430566; Object Layer Attributes #3, Jednotka: m2; Object Layer Attributes #3, Název_objektu: Stěna; Pset_WallCommon - LoadBearing: yes
ZELEZOBETONOVÁ KCE | Půdorys 1.PP | ZELEZOBETONOVÁ KCE 0.25 m, LIGNOPOR 0.025 m, PÓROBETONOVÉ ZDIVO 0.08 m |  | ZELEZOBETONOVÁ KCE | A | 1352HWa0000003713 | m3 | Celá stěna | Stávající | Betonářské práce | ZELEZOBETONOVÁ KCE |  | 1352Stě0000003714 | m3 | Stěna | 0 | 0.355 | 5.412 | 5.251 | 1.452 | 1.265 | 1.437 | 0.418 | 3.95 | NEMSOK - Object Layer Attributes #2, 2D interakce: yes; Object Layer Attributes #2, Status: Stávající; Object Layer Attributes #2, Práce: Zateplovací systémy; Object Layer Attributes #2, Materiál: LIGNOPOR; Object Layer Attributes #2, Allright_Stavebni_dil_ID: 1352Stě0000003715; Object Layer Attributes #2, Jednotka: m2; Object Layer Attributes #2, Název_objektu: Stěna; Object Layer Attributes #3, 2D interakce: yes; Object Layer Attributes #3, Status: Stávající; Object Layer Attributes #3, Práce: Zednické práce; Object Layer Attributes #3, Materiál: PÓROBETONOVÉ ZDIVO; Object Layer Attributes #3, Allright_Stavebni_dil_ID: 1352Stě0798430280; Object Layer Attributes #3, Jednotka: m2; Object Layer Attributes #3, Název_objektu: Stěna; Pset_WallCommon - LoadBearing: yes
ZELEZOBETONOVÁ KCE | Půdorys 1.PP | ZELEZOBETONOVÁ KCE 0.2 m, LIGNOPOR 0.025 m, PÓROBETONOVÉ ZDIVO 0.08 m |  | ZELEZOBETONOVÁ KCE | A | 1352HWa0000003734 | m3 | Celá stěna | Stávající | Betonářské práce | ZELEZOBETONOVÁ KCE |  | 1352Stě0000003735 | m3 | Stěna | 0 | 0.305 | 13.904 | 13.904 | 3.654 | 3.498 | 3.654 | 1.051 | 3.95 | NEMSOK - Object Layer Attributes #2, 2D interakce: yes; Object Layer Attributes #2, Status: Stávající; Object Layer Attributes #2, Práce: Zateplovací systémy; Object Layer Attributes #2, Materiál: LIGNOPOR; Object Layer Attributes #2, Allright_Stavebni_dil_ID: 1352Stě0000003736; Object Layer Attributes #2, Jednotka: m2; Object Layer Attributes #2, Název_objektu: Stěna; Object Layer Attributes #3, 2D interakce: yes; Object Layer Attributes #3, Status: Stávající; Object Layer Attributes #3, Práce: Zednické práce; Object Layer Attributes #3, Materiál: PÓROBETONOVÉ ZDIVO; Object Layer Attributes #3, Allright_Stavebni_dil_ID: 1352Stě0798430436; Object Layer Attributes #3, Jednotka: m2; Object Layer Attributes #3, Název_objektu: Stěna; Pset_WallCommon - LoadBearing: yes
ZELEZOBETONOVÁ KCE | Půdorys 1.PP | ZELEZOBETONOVÁ KCE |  | ZELEZOBETONOVÁ KCE | A | 1352HWa0000002694 | m3 | Celá stěna | Stávající | Betonářské práce | ZELEZOBETONOVÁ KCE |  | 1352Stě0000002695 | m3 | Stěna | 0 | 0.555 | 23.108 | 18.398 | 11.099 | 5.85 | 10.095 | 3.247 | 3.95 | NEMSOK - Object Layer Attributes #2, 2D interakce: yes; Object Layer Attributes #2, Status: Stávající; Object Layer Attributes #2, Práce: Zateplovací systémy; Object Layer Attributes #2, Materiál: LIGNOPOR; Object Layer Attributes #2, Allright_Stavebni_dil_ID: 1352Stě0000002696; Object Layer Attributes #2, Jednotka: m2; Object Layer Attributes #2, Název_objektu: Stěna; Object Layer Attributes #3, 2D interakce: yes; Object Layer Attributes #3, Status: Stávající; Object Layer Attributes #3, Práce: Zednické práce; Object Layer Attributes #3, Materiál: PÓROBETONOVÉ ZDIVO; Object Layer Attributes #3, Allright_Stavebni_dil_ID: 1352Stě0798429592; Object Layer Attributes #3, Jednotka: m2; Object Layer Attributes #3, Název_objektu: Stěna; Pset_WallCommon - LoadBearing: yes
ZELEZOBETONOVÁ KCE | Půdorys 1.PP | ZELEZOBETONOVÁ KCE 0.65 m, LIGNOPOR 0.025 m, PÓROBETONOVÉ ZDIVO 0.08 m |  | ZELEZOBETONOVÁ KCE | A | 1352HWa0000002702 | m3 | Celá stěna | Stávající | Betonářské práce | ZELEZOBETONOVÁ KCE |  | 1352Stě0000002703 | m3 | Stěna | 0 | 0.755 | 13.746 | 13.746 | 8.499 | 3.413 | 8.499 | 2.497 | 3.95 | NEMSOK - Object Layer Attributes #2, 2D interakce: yes; Object Layer Attributes #2, Status: Stávající; Object Layer Attributes #2, Práce: Zateplovací systémy; Object Layer Attributes #2, Materiál: LIGNOPOR; Object Layer Attributes #2, Allright_Stavebni_dil_ID: 1352Stě0000002704; Object Layer Attributes #2, Jednotka: m2; Object Layer Attributes #2, Název_objektu: Stěna; Object Layer Attributes #3, 2D interakce: yes; Object Layer Attributes #3, Status: Stávající; Object Layer Attributes #3, Práce: Zednické práce; Object Layer Attributes #3, Materiál: PÓROBETONOVÉ ZDIVO; Object Layer Attributes #3, Allright_Stavebni_dil_ID: 1352Stě0798429496; Object Layer Attributes #3, Jednotka: m2; Object Layer Attributes #3, Název_objektu: Stěna; Pset_WallCommon - LoadBearing: yes
ZELEZOBETONOVÁ KCE | Půdorys 1.PP | ZELEZOBETONOVÁ KCE 0.65 m, LIGNOPOR 0.025 m, PÓROBETONOVÉ ZDIVO 0.08 m |  | ZELEZOBETONOVÁ KCE | A | 1352HWa0000002721 | m3 | Celá stěna | Stávající | Betonářské práce | ZELEZOBETONOVÁ KCE |  | 1352Stě0000002722 | m3 | Stěna | 0 | 0.755 | 3.015 | 3.015 | 2.182 | 0.668 | 2.159 | 0.645 | 3.95 | NEMSOK - Object Layer Attributes #2, 2D interakce: yes; Object Layer Attributes #2, Status: Stávající; Object Layer Attributes #2, Práce: Zateplovací systémy; Object Layer Attributes #2, Materiál: LIGNOPOR; Object Layer Attributes #2, Allright_Stavebni_dil_ID: 1352Stě0000002723; Object Layer Attributes #2, Jednotka: m2; Object Layer Attributes #2, Název_objektu: Stěna; Object Layer Attributes #3, 2D interakce: yes; Object Layer Attributes #3, Status: Stávající; Object Layer Attributes #3, Práce: Zednické práce; Object Layer Attributes #3, Materiál: PÓROBETONOVÉ ZDIVO; Object Layer Attributes #3, Allright_Stavebni_dil_ID: 1352Stě0798429904; Object Layer Attributes #3, Jednotka: m2; Object Layer Attributes #3, Název_objektu: Stěna; Pset_WallCommon - LoadBearing: yes
ZELEZOBETONOVÁ KCE | Půdorys 1.PP | ZELEZOBETONOVÁ KCE 0.4 m, LIGNOPOR 0.025 m, PÓROBETONOVÉ ZDIVO 0.08 m | 1 | ZELEZOBETONOVÁ KCE | A | 1352HWa0798500752 | m3 | Celá stěna | Stávající | Betonářské práce | ZELEZOBETONOVÁ KCE | no | 1352Stě0798500756 | m3 | Stěna | 0 | 0.505 | 30.673 | 30.674 | 14.282 | 9.295 | 14.282 | 4.694 | 3.3 | NEMSOK - Object Layer Attributes #2, 2D interakce: yes; Object Layer Attributes #2, Status: Stávající; Object Layer Attributes #2, Práce: Zateplovací systémy; Object Layer Attributes #2, Materiál: LIGNOPOR; Object Layer Attributes #2, Allright_Stavebni_dil_ID: 1352Stě0798500755; Object Layer Attributes #2, Jednotka: m2; Object Layer Attributes #2, Název_objektu: Stěna; Object Layer Attributes #3, 2D interakce: yes; Object Layer Attributes #3, Status: Stávající; Object Layer Attributes #3, Práce: Zednické práce; Object Layer Attributes #3, Materiál: PÓROBETONOVÉ ZDIVO; Object Layer Attributes #3, Allright_Stavebni_dil_ID: 1352Stě0798500754; Object Layer Attributes #3, Jednotka: m2; Object Layer Attributes #3, Název_objektu: Stěna; Object Layer Attributes #2, Staticky nosná konstrukce: no; Object Layer Attributes #3, Staticky nosná konstrukce: no; Pset_WallCommon - LoadBearing: yes
ZELEZOBETONOVÁ KCE | Půdorys 1.PP | ZELEZOBETONOVÁ KCE 0.4 m, LIGNOPOR 0.025 m, PÓROBETONOVÉ ZDIVO 0.08 m |  | ZELEZOBETONOVÁ KCE | A | 1352HWa0000003048 | m3 | Celá stěna | Stávající | Betonářské práce | ZELEZOBETONOVÁ KCE | no | 1352Stě0000003049 | m3 | Stěna | 0 | 0.505 | 9.136 | 9.066 | 4.364 | 2.855 | 4.358 | 1.442 | 3.2 | NEMSOK - Object Layer Attributes #2, 2D interakce: yes; Object Layer Attributes #2, Status: Stávající; Object Layer Attributes #2, Práce: Zateplovací systémy; Object Layer Attributes #2, Materiál: LIGNOPOR; Object Layer Attributes #2, Allright_Stavebni_dil_ID: 1352Stě0798461550; Object Layer Attributes #2, Jednotka: m2; Object Layer Attributes #2, Název_objektu: Stěna; Object Layer Attributes #3, 2D interakce: yes; Object Layer Attributes #3, Status: Stávající; Object Layer Attributes #3, Práce: Zednické práce; Object Layer Attributes #3, Materiál: PÓROBETONOVÉ ZDIVO; Object Layer Attributes #3, Allright_Stavebni_dil_ID: 1352Stě0798461551; Object Layer Attributes #3, Jednotka: m2; Object Layer Attributes #3, Název_objektu: Stěna; Object Layer Attributes #2, Staticky nosná konstrukce: no; Object Layer Attributes #3, Staticky nosná konstrukce: no; Pset_WallCommon - LoadBearing: yes
ZELEZOBETONOVÁ KCE | Půdorys 1.PP | ZELEZOBETONOVÁ KCE 0.2 m, LIGNOPOR 0.025 m, PÓROBETONOVÉ ZDIVO 0.08 m |  | ZELEZOBETONOVÁ KCE | A | 1352HWa0798430703 | m3 | Celá stěna | Stávající | Betonářské práce | ZELEZOBETONOVÁ KCE |  | 1352Stě0798430711 | m3 | Stěna | 0 | 0.305 | 8.69 | 8.69 | 2.331 | 2.2 | 2.331 | 0.671 | 3.95 | NEMSOK - Object Layer Attributes #2, 2D interakce: yes; Object Layer Attributes #2, Status: Stávající; Object Layer Attributes #2, Práce: Zateplovací systémy; Object Layer Attributes #2, Materiál: LIGNOPOR; Object Layer Attributes #2, Allright_Stavebni_dil_ID: 1352Stě0798430710; Object Layer Attributes #2, Jednotka: m2; Object Layer Attributes #2, Název_objektu: Stěna; Object Layer Attributes #3, 2D interakce: yes; Object Layer Attributes #3, Status: Stávající; Object Layer Attributes #3, Práce: Zednické práce; Object Layer Attributes #3, Materiál: PÓROBETONOVÉ ZDIVO; Object Layer Attributes #3, Allright_Stavebni_dil_ID: 1352Stě0798430709; Object Layer Attributes #3, Jednotka: m2; Object Layer Attributes #3, Název_objektu: Stěna; Pset_WallCommon - LoadBearing: yes
ZELEZOBETONOVÁ KCE | Půdorys 1.PP | ZELEZOBETONOVÁ KCE 0.2 m, LIGNOPOR 0.025 m, PÓROBETONOVÉ ZDIVO 0.08 m |  | ZELEZOBETONOVÁ KCE | A | 1352HWa0000003680 | m3 | Celá stěna | Stávající | Betonářské práce | ZELEZOBETONOVÁ KCE |  | 1352Stě0000003681 | m3 | Stěna | 0 | 0.305 | 29.842 | 29.842 | 7.93 | 7.493 | 7.93 | 2.281 | 3.95 | NEMSOK - Object Layer Attributes #2, 2D interakce: yes; Object Layer Attributes #2, Status: Stávající; Object Layer Attributes #2, Práce: Zateplovací systémy; Object Layer Attributes #2, Materiál: LIGNOPOR; Object Layer Attributes #2, Allright_Stavebni_dil_ID: 1352Stě0000003682; Object Layer Attributes #2, Jednotka: m2; Object Layer Attributes #2, Název_objektu: Stěna; Object Layer Attributes #3, 2D interakce: yes; Object Layer Attributes #3, Status: Stávající; Object Layer Attributes #3, Práce: Zednické práce; Object Layer Attributes #3, Materiál: PÓROBETONOVÉ ZDIVO; Object Layer Attributes #3, Allright_Stavebni_dil_ID: 1352Stě0798431478; Object Layer Attributes #3, Jednotka: m2; Object Layer Attributes #3, Název_objektu: Stěna; Pset_WallCommon - LoadBearing: yes
ZELEZOBETONOVÁ KCE | Půdorys 1.PP | ZELEZOBETONOVÁ KCE |  | ZELEZOBETONOVÁ KCE | A | 1352HWa0000003844 | m3 | Celá stěna | Stávající | Betonářské práce | ZELEZOBETONOVÁ KCE |  | 1352Stě0000003845 | m3 | Stěna | 0 | 0.555 | 5.017 | 5.017 | 2.233 | 1.25 | 2.233 | 0.652 | 3.95 | NEMSOK - Object Layer Attributes #2, 2D interakce: yes; Object Layer Attributes #2, Status: Stávající; Object Layer Attributes #2, Práce: Zateplovací systémy; Object Layer Attributes #2, Materiál: LIGNOPOR; Object Layer Attributes #2, Allright_Stavebni_dil_ID: 1352Stě0798431531; Object Layer Attributes #2, Jednotka: m2; Object Layer Attributes #2, Název_objektu: Stěna; Object Layer Attributes #3, 2D interakce: yes; Object Layer Attributes #3, Status: Stávající; Object Layer Attributes #3, Práce: Zednické práce; Object Layer Attributes #3, Materiál: PÓROBETONOVÉ ZDIVO; Object Layer Attributes #3, Allright_Stavebni_dil_ID: 1352Stě0798435982; Object Layer Attributes #3, Jednotka: m2; Object Layer Attributes #3, Název_objektu: Stěna; Pset_WallCommon - LoadBearing: yes
ZELEZOBETONOVÁ KCE | Půdorys 1.PP | ZELEZOBETONOVÁ KCE 0.65 m, LIGNOPOR 0.025 m, PÓROBETONOVÉ ZDIVO 0.08 m |  | ZELEZOBETONOVÁ KCE | A | 1352HWa0000003618 | m3 | Celá stěna | Stávající | Betonářské práce | ZELEZOBETONOVÁ KCE |  | 1352Stě0000003619 | m3 | Stěna | 0 | 0.755 | 14.042 | 12.532 | 8.892 | 3.493 | 8.738 | 2.614 | 3.95 | NEMSOK - Object Layer Attributes #2, 2D interakce: yes; Object Layer Attributes #2, Status: Stávající; Object Layer Attributes #2, Práce: Zateplovací systémy; Object Layer Attributes #2, Materiál: LIGNOPOR; Object Layer Attributes #2, Allright_Stavebni_dil_ID: 1352Stě0798431620; Object Layer Attributes #2, Jednotka: m2; Object Layer Attributes #2, Název_objektu: Stěna; Object Layer Attributes #3, 2D interakce: yes; Object Layer Attributes #3, Status: Stávající; Object Layer Attributes #3, Práce: Zednické práce; Object Layer Attributes #3, Materiál: PÓROBETONOVÉ ZDIVO; Object Layer Attributes #3, Allright_Stavebni_dil_ID: 1352Stě0798457435; Object Layer Attributes #3, Jednotka: m2; Object Layer Attributes #3, Název_objektu: Stěna; Pset_WallCommon - LoadBearing: yes
ZDIVO Z CDm | Půdorys 1.PP | ZDIVO Z CDm 0.25 m |  | ZDIVO Z CDm | REI 120 | 1352HWa0798436736 | m3 | Celá stěna | Stávající | Zednické práce | ZDIVO Z CDm | no | 1352Stě0798436737 | m3 | Stěna | 0.22 | 0.25 | 17.4 | 9.242 | 4.35 | 5.705 | 2.311 | 1.426 | 3.05 | Pset_WallCommon - AcousticRating: 47 dB
ZELEZOBETONOVÁ KCE | Půdorys 1.PP | ZELEZOBETONOVÁ KCE 0.2 m |  | ZELEZOBETONOVÁ KCE | A | 1352HWa0000005338 | m3 | Celá stěna | Stávající | Betonářské práce | ZELEZOBETONOVÁ KCE | yes | 1352Stě0000005339 | m3 | Stěna | 0 | 0.2 | 42.884 | 42.884 | 8.577 | 11.345 | 8.577 | 2.269 | 3.78
PÓROBETONOVÉ ZDIVO | Půdorys 1.PP | PÓROBETONOVÉ ZDIVO 0.1 m |  | PÓROBETONOVÉ ZDIVO | EI 120 | 1352HWa0798428037 | m3 | Celá stěna | Stávající | Zednické práce | PÓROBETONOVÉ ZDIVO |  | 1352Stě0798428038 | m2 | Stěna | 1.111 | 0.1 | 2.97 | 2.97 | 0.297 | 2.7 | 0.297 | 0.27 | 1.1 | Pset_WallCommon - AcousticRating: 37 dB
PÓROBETONOVÉ ZDIVO | Půdorys 1.PP | PÓROBETONOVÉ ZDIVO 0.1 m |  | PÓROBETONOVÉ ZDIVO | EI 120 | 1352HWa0798428108 | m3 | Celá stěna | Stávající | Zednické práce | PÓROBETONOVÉ ZDIVO |  | 1352Stě0798428110 | m2 | Stěna | 1.111 | 0.1 | 2.97 | 2.97 | 0.297 | 2.7 | 0.297 | 0.27 | 1.1 | Pset_WallCommon - AcousticRating: 37 dB
PÓROBETONOVÉ ZDIVO | Půdorys 1.PP | PÓROBETONOVÉ ZDIVO 0.1 m |  | PÓROBETONOVÉ ZDIVO | EI 120 | 1352HWa0798438178 | m3 | Celá stěna | Stávající | Zednické práce | PÓROBETONOVÉ ZDIVO |  | 1352Stě0798438179 | m2 | Stěna | 1.111 | 0.1 | 2.833 | 2.833 | 0.283 | 2.575 | 0.283 | 0.257 | 1.1 | Pset_WallCommon - AcousticRating: 37 dB
PÓROBETONOVÉ ZDIVO | Půdorys 1.PP | PÓROBETONOVÉ ZDIVO 0.1 m | 1 | PÓROBETONOVÉ ZDIVO | EI 120 | 1352HWa0798443005 | m3 | Celá stěna | Stávající | Zednické práce | PÓROBETONOVÉ ZDIVO |  | 1352Stě0798443006 | m2 | Stěna | 1.111 | 0.1 | 5.261 | 2.111 | 0.526 | 1.725 | 0.211 | 0.173 | 3.05 | Pset_WallCommon - AcousticRating: 37 dB
ZELEZOBETONOVÁ KCE | Půdorys 1.PP | ZELEZOBETONOVÁ KCE 0.2 m, LIGNOPOR 0.025 m, PÓROBETONOVÉ ZDIVO 0.08 m |  | ZELEZOBETONOVÁ KCE | A | 1352HWa0798495497 | m3 | Celá stěna | Stávající | Betonářské práce | ZELEZOBETONOVÁ KCE |  | 1352Stě0798495518 | m3 | Stěna | 0 | 0.305 | 25.628 | 22.928 | 6.393 | 7.65 | 5.786 | 2.333 | 3.35 | NEMSOK - Object Layer Attributes #2, 2D interakce: yes; Object Layer Attributes #2, Status: Stávající; Object Layer Attributes #2, Práce: Zateplovací systémy; Object Layer Attributes #2, Materiál: LIGNOPOR; Object Layer Attributes #2, Allright_Stavebni_dil_ID: 1352Stě0798495520; Object Layer Attributes #2, Jednotka: m2; Object Layer Attributes #2, Název_objektu: Stěna; Object Layer Attributes #3, 2D interakce: yes; Object Layer Attributes #3, Status: Stávající; Object Layer Attributes #3, Práce: Zednické práce; Object Layer Attributes #3, Materiál: PÓROBETONOVÉ ZDIVO; Object Layer Attributes #3, Allright_Stavebni_dil_ID: 1352Stě0798495519; Object Layer Attributes #3, Jednotka: m2; Object Layer Attributes #3, Název_objektu: Stěna; Pset_WallCommon - LoadBearing: yes
ZELEZOBETONOVÁ KCE | Půdorys 1.PP | ZELEZOBETONOVÁ KCE 0.4 m, LIGNOPOR 0.025 m, PÓROBETONOVÉ ZDIVO 0.08 m |  | ZELEZOBETONOVÁ KCE | A | 1352HWa0798460925 | m3 | Celá stěna | Stávající | Betonářské práce | ZELEZOBETONOVÁ KCE | no | 1352Stě0798460926 | m3 | Stěna | 0 | 0.505 | 32.257 | 32.227 | 14.627 | 9.658 | 14.612 | 4.806 | 3.3 | NEMSOK - Object Layer Attributes #2, 2D interakce: yes; Object Layer Attributes #2, Status: Stávající; Object Layer Attributes #2, Práce: Zateplovací systémy; Object Layer Attributes #2, Materiál: LIGNOPOR; Object Layer Attributes #2, Allright_Stavebni_dil_ID: 1352Stě0798461814; Object Layer Attributes #2, Jednotka: m2; Object Layer Attributes #2, Název_objektu: Stěna; Object Layer Attributes #3, 2D interakce: yes; Object Layer Attributes #3, Status: Stávající; Object Layer Attributes #3, Práce: Zednické práce; Object Layer Attributes #3, Materiál: PÓROBETONOVÉ ZDIVO; Object Layer Attributes #3, Allright_Stavebni_dil_ID: 1352Stě0798461815; Object Layer Attributes #3, Jednotka: m2; Object Layer Attributes #3, Název_objektu: Stěna; Object Layer Attributes #2, Staticky nosná konstrukce: no; Object Layer Attributes #3, Staticky nosná konstrukce: no; Pset_WallCommon - LoadBearing: yes
PÓROBETONOVÉ ZDIVO | Půdorys 1.PP | PÓROBETONOVÉ ZDIVO | 1 | PÓROBETONOVÉ ZDIVO | EI 120 | 1352HWa0798459069 | m3 | Celá stěna | Stávající | Zednické práce | PÓROBETONOVÉ ZDIVO |  | 1352Stě0798459070 | m2 | Stěna | 1.111 | 0.1 | 36.356 | 30.11 | 3.636 | 11.92 | 3.011 | 1.192 | 3.05 | Pset_WallCommon - AcousticRating: 37 dB
ZDIVO Z CDm | Půdorys 1.PP | ZDIVO Z CDm 0.125 m | 1 | ZDIVO Z CDm | A | 1352HWa0798442921 | m3 | Celá stěna | Stávající | Zednické práce | ZDIVO Z CDm | yes | 1352Stě0798442922 | m3 | Stěna | 0 | 0.125 | 20.816 | 18.716 | 2.602 | 6.825 | 2.385 | 0.853 | 3.05
ZDIVO Z CDm | Půdorys 1.PP | ZDIVO Z CDm |  | ZDIVO Z CDm | A | 1352HWa0798450112 | m3 | Celá stěna | Stávající | Zednické práce | ZDIVO Z CDm | yes | 1352Stě0798450113 | m3 | Stěna | 0 | 0.125 | 69.616 | 55.03 | 8.702 | 22.825 | 6.879 | 2.853 | 3.05
ZDIVO Z CDm | Půdorys 1.PP | ZDIVO Z CDm 0.125 m | 1 | ZDIVO Z CDm | A | 1352HWa0798442956 | m3 | Celá stěna | Stávající | Zednické práce | ZDIVO Z CDm | yes | 1352Stě0798442957 | m3 | Stěna | 0 | 0.125 | 19.978 | 19.683 | 2.497 | 6.55 | 2.46 | 0.819 | 3.05
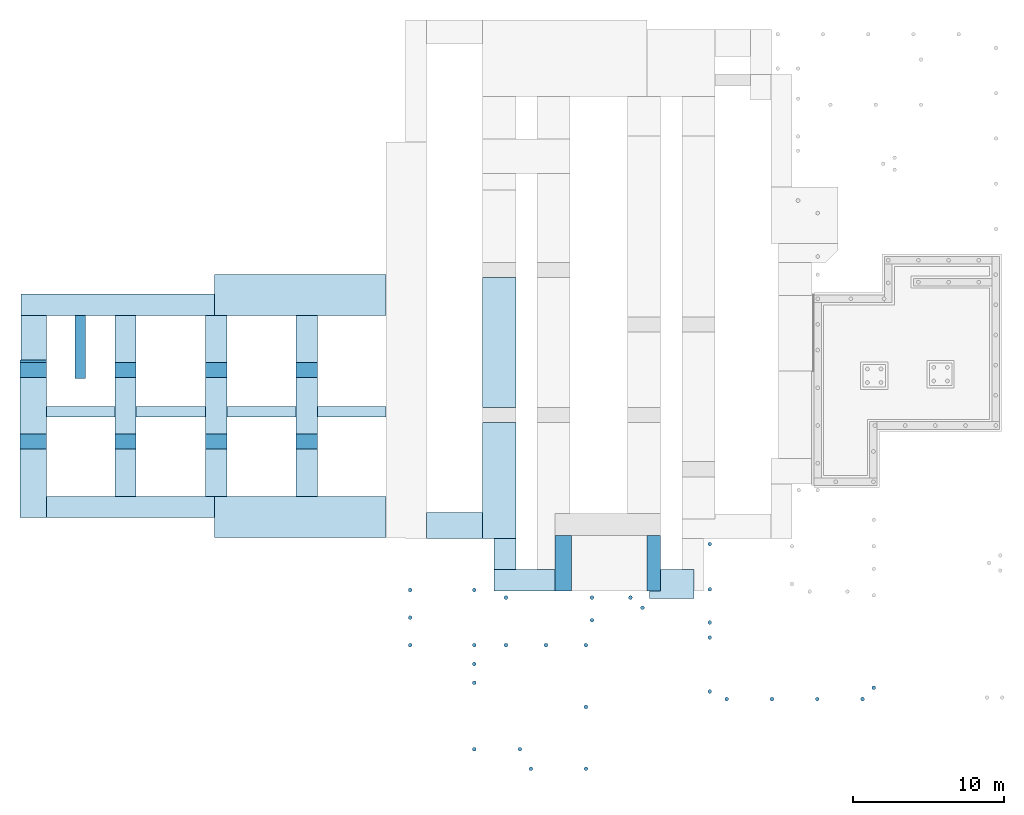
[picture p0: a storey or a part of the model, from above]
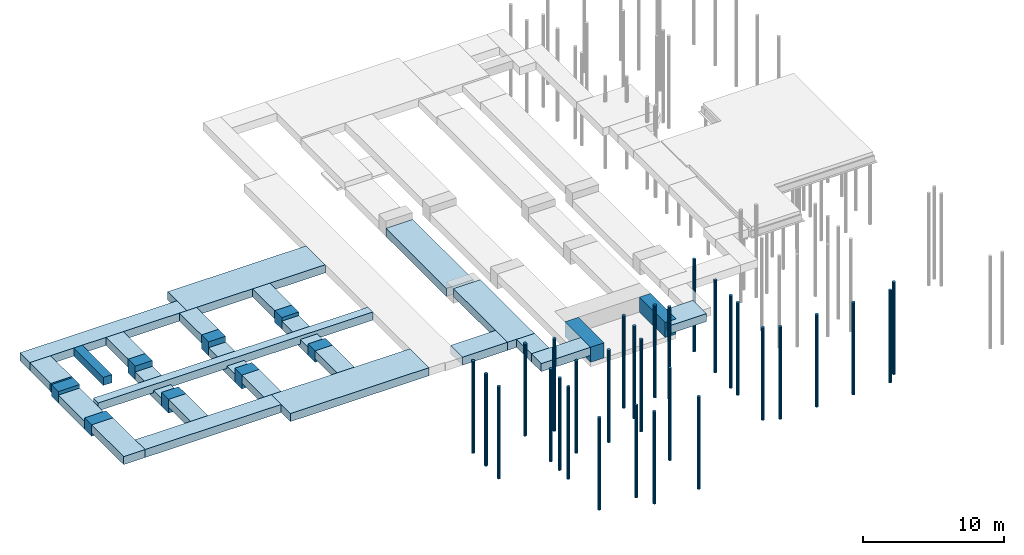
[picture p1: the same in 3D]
Properties of the parts of a building model (IFC4), part 27 of 45

# IfcWall (2385)
Name | In | Material | Faktor | Označení | Požární odolnost | Allright_Stavebni_dil_ID | Jednotka | Název_objektu | Object Layer Attributes #1, Status | Object Layer Attributes #1, Práce | Object Layer Attributes #1, Materiál | Object Layer Attributes #1, Staticky nosná konstrukce | Object Layer Attributes #1, Allright_Stavebni_dil_ID | Object Layer Attributes #1, Jednotka | Object Layer Attributes #1, Název_objektu | ThermalTransmittance (W/K/m2) | Width (m) | GrossSideArea (m2) | NetSideArea (m2) | GrossVolume (m3) | Length (m) | NetVolume (m3) | GrossFootprintArea (m2) | Height (m)
PÓROBETONOVÉ ZDIVO | Půdorys 1.PP | PÓROBETONOVÉ ZDIVO 0.1 m | 1 | PÓROBETONOVÉ ZDIVO | EI 120 | 1352HWa0798443173 | m3 | Celá stěna | Stávající | Zednické práce | PÓROBETONOVÉ ZDIVO |  | 1352Stě0798443174 | m2 | Stěna | 1.111 | 0.1 | 9.76 | 9.715 | 0.976 | 3.2 | 0.971 | 0.32 | 3.05 | Pset_WallCommon - AcousticRating: 37 dB
PÓROBETONOVÉ ZDIVO | Půdorys 1.PP | PÓROBETONOVÉ ZDIVO 0.1 m | 1 | PÓROBETONOVÉ ZDIVO | EI 120 | 1352HWa0798502471 | m3 | Celá stěna | Stávající | Zednické práce | PÓROBETONOVÉ ZDIVO |  | 1352Stě0798502476 | m2 | Stěna | 1.111 | 0.1 | 3.05 | 1.475 | 0.305 | 1 | 0.147 | 0.1 | 3.05 | Pset_WallCommon - AcousticRating: 37 dB
PÓROBETONOVÉ ZDIVO | Půdorys 1.PP | PÓROBETONOVÉ ZDIVO 0.1 m |  | PÓROBETONOVÉ ZDIVO | EI 120 | 1352HWa0798441374 | m3 | Celá stěna | Stávající | Zednické práce | PÓROBETONOVÉ ZDIVO |  | 1352Stě0798441375 | m2 | Stěna | 1.111 | 0.1 | 3.203 | 3.203 | 0.32 | 1.525 | 0.32 | 0.152 | 2.1 | Pset_WallCommon - AcousticRating: 37 dB
 | Půdorys 1.PP | ZELEZOBETONOVÁ KCE 0.5 m |  |  |  | 1354HWa0000000008 | m3 | Celá stěna | Stávající | Betonářské práce | ZELEZOBETONOVÁ KCE | yes | 1354Ven0000000043 | m2 | Věnec |  | 0.5 | 1.888 | 1.888 | 0.944 | 0 | 0.944 | 3.775 | 0.25
 | Půdorys 1.PP | ZELEZOBETONOVÁ KCE 0.5 m |  |  |  | 1354HWa0000000009 | m3 | Celá stěna | Stávající | Betonářské práce | ZELEZOBETONOVÁ KCE | yes | 1354Ven0000000051 | m2 | Věnec |  | 0.5 | 1.888 | 1.888 | 0.944 | 0 | 0.944 | 3.775 | 0.25
 | Půdorys 1.PP | ZELEZOBETONOVÁ KCE 0.5 m |  |  |  | 1354HWa0000000038 | m3 | Celá stěna | Stávající | Betonářské práce | ZELEZOBETONOVÁ KCE | yes | 1354Ven0000000041 | m2 | Věnec |  | 0.5 | 0.75 | 0.75 | 0.375 | 0 | 0.375 | 1.5 | 0.25
 | Půdorys 1.PP | ZELEZOBETONOVÁ KCE 0.5 m | 1 |  |  | 1354HWa0000000007 | m3 | Celá stěna | Stávající | Betonářské práce | ZELEZOBETONOVÁ KCE | yes | 1354Ven0000000053 | m2 | Věnec |  | 0.5 | 2.375 | 2.375 | 1.188 | 0 | 1.188 | 4.75 | 0.25
 | Půdorys 1.PP | ZELEZOBETONOVÁ KCE 0.2 m, LIGNOPOR 0.025 m |  |  |  | 1354HWa0000001257 | m3 | Celá stěna | Stávající | Betonářské práce | ZELEZOBETONOVÁ KCE |  | 1354Ven0000001258 | m2 | Věnec |  | 0.225 | 6.375 | 6.375 | 1.432 | 0 | 1.432 | 5.728 | 0.25 | NEMSOK - Object Layer Attributes #2, 2D interakce: yes; Object Layer Attributes #2, Status: Stávající; Object Layer Attributes #2, Práce: Zateplovací systémy; Object Layer Attributes #2, Materiál: LIGNOPOR; Object Layer Attributes #2, Allright_Stavebni_dil_ID: 1354Ven0000001259; Object Layer Attributes #2, Jednotka: m2; Object Layer Attributes #2, Název_objektu: Věnec
 | Půdorys 1.PP | ZELEZOBETONOVÁ KCE 0.25 m, LIGNOPOR 0.025 m |  |  |  | 1354HWa0000001327 | m3 | Celá stěna | Stávající | Betonářské práce | ZELEZOBETONOVÁ KCE |  | 1354Ven0000001328 | m2 | Věnec |  | 0.275 | 1.106 | 1.106 | 0.303 | 0 | 0.303 | 1.211 | 0.25 | NEMSOK - Object Layer Attributes #2, 2D interakce: yes; Object Layer Attributes #2, Status: Stávající; Object Layer Attributes #2, Práce: Zateplovací systémy; Object Layer Attributes #2, Materiál: LIGNOPOR; Object Layer Attributes #2, Allright_Stavebni_dil_ID: 1354Ven0000001329; Object Layer Attributes #2, Jednotka: m2; Object Layer Attributes #2, Název_objektu: Věnec
 | Půdorys 1.PP | ZELEZOBETONOVÁ KCE 0.2 m, LIGNOPOR 0.025 m | 1 |  |  | 1354HWa0000001377 | m3 | Celá stěna | Stávající | Betonářské práce | ZELEZOBETONOVÁ KCE |  | 1354Ven0000001378 | m2 | Věnec |  | 0.225 | 6.438 | 6.438 | 1.447 | 0 | 1.447 | 5.789 | 0.25 | NEMSOK - Object Layer Attributes #2, 2D interakce: yes; Object Layer Attributes #2, Status: Stávající; Object Layer Attributes #2, Práce: Zateplovací systémy; Object Layer Attributes #2, Materiál: LIGNOPOR; Object Layer Attributes #2, Allright_Stavebni_dil_ID: 1354Ven0000001379; Object Layer Attributes #2, Jednotka: m2; Object Layer Attributes #2, Název_objektu: Věnec
 | Půdorys 1.PP | ZELEZOBETONOVÁ KCE 0.2 m, LIGNOPOR 0.025 m | 1 |  |  | 1354HWa0000001405 | m3 | Celá stěna | Stávající | Betonářské práce | ZELEZOBETONOVÁ KCE |  | 1354Ven0000001406 | m2 | Věnec |  | 0.225 | 0.342 | 0.343 | 0.077 | 0 | 0.077 | 0.308 | 0.25 | NEMSOK - Object Layer Attributes #2, 2D interakce: yes; Object Layer Attributes #2, Status: Stávající; Object Layer Attributes #2, Práce: Zateplovací systémy; Object Layer Attributes #2, Materiál: LIGNOPOR; Object Layer Attributes #2, Allright_Stavebni_dil_ID: 1354Ven0000001407; Object Layer Attributes #2, Jednotka: m2; Object Layer Attributes #2, Název_objektu: Věnec
 | Půdorys 1.PP | ZELEZOBETONOVÁ KCE 0.27 m, LIGNOPOR 0.025 m | 1 |  |  | 1354HWa0000001446 | m3 | Celá stěna | Stávající | Betonářské práce | ZELEZOBETONOVÁ KCE |  | 1354Ven0000001447 | m2 | Věnec |  | 0.295 | 1.575 | 1.575 | 0.462 | 0 | 0.462 | 1.847 | 0.25 | NEMSOK - Object Layer Attributes #2, 2D interakce: yes; Object Layer Attributes #2, Status: Stávající; Object Layer Attributes #2, Práce: Zateplovací systémy; Object Layer Attributes #2, Materiál: LIGNOPOR; Object Layer Attributes #2, Allright_Stavebni_dil_ID: 1354Ven0000001448; Object Layer Attributes #2, Jednotka: m2; Object Layer Attributes #2, Název_objektu: Věnec
 | Půdorys 1.PP | ZELEZOBETONOVÁ KCE 0.65 m, LIGNOPOR 0.025 m | 1 |  |  | 1354HWa0000001469 | m3 | Celá stěna | Stávající | Betonářské práce | ZELEZOBETONOVÁ KCE |  | 1354Ven0000001470 | m2 | Věnec |  | 0.675 | 0.87 | 0.87 | 0.587 | 0 | 0.587 | 2.349 | 0.25 | NEMSOK - Object Layer Attributes #2, 2D interakce: yes; Object Layer Attributes #2, Status: Stávající; Object Layer Attributes #2, Práce: Zateplovací systémy; Object Layer Attributes #2, Materiál: LIGNOPOR; Object Layer Attributes #2, Allright_Stavebni_dil_ID: 1354Ven0000001471; Object Layer Attributes #2, Jednotka: m2; Object Layer Attributes #2, Název_objektu: Věnec
 | Půdorys 1.PP | ZELEZOBETONOVÁ KCE 0.65 m, LIGNOPOR 0.025 m | 1 |  |  | 1354HWa0000001496 | m3 | Celá stěna | Stávající | Betonářské práce | ZELEZOBETONOVÁ KCE |  | 1354Ven0000001497 | m2 | Věnec |  | 0.675 | 3.481 | 3.481 | 2.24 | 0 | 2.24 | 8.961 | 0.25 | NEMSOK - Object Layer Attributes #2, 2D interakce: yes; Object Layer Attributes #2, Status: Stávající; Object Layer Attributes #2, Práce: Zateplovací systémy; Object Layer Attributes #2, Materiál: LIGNOPOR; Object Layer Attributes #2, Allright_Stavebni_dil_ID: 1354Ven0000001498; Object Layer Attributes #2, Jednotka: m2; Object Layer Attributes #2, Název_objektu: Věnec
 | Půdorys 1.PP | ZELEZOBETONOVÁ KCE 0.65 m, LIGNOPOR 0.025 m | 1 |  |  | 1354HWa0000001522 | m3 | Celá stěna | Stávající | Betonářské práce | ZELEZOBETONOVÁ KCE |  | 1354Ven0000001523 | m2 | Věnec |  | 0.675 | 0.87 | 0.87 | 0.555 | 0 | 0.555 | 2.219 | 0.25 | NEMSOK - Object Layer Attributes #2, 2D interakce: yes; Object Layer Attributes #2, Status: Stávající; Object Layer Attributes #2, Práce: Zateplovací systémy; Object Layer Attributes #2, Materiál: LIGNOPOR; Object Layer Attributes #2, Allright_Stavebni_dil_ID: 1354Ven0000001524; Object Layer Attributes #2, Jednotka: m2; Object Layer Attributes #2, Název_objektu: Věnec
 | Půdorys 1.PP | ZELEZOBETONOVÁ KCE 0.45 m, LIGNOPOR 0.025 m | 1 |  |  | 1354HWa0000001551 | m3 | Celá stěna | Stávající | Betonářské práce | ZELEZOBETONOVÁ KCE |  | 1354Ven0000001552 | m2 | Věnec |  | 0.475 | 1.463 | 1.463 | 0.695 | 0 | 0.695 | 2.779 | 0.25 | NEMSOK - Object Layer Attributes #2, 2D interakce: yes; Object Layer Attributes #2, Status: Stávající; Object Layer Attributes #2, Práce: Zateplovací systémy; Object Layer Attributes #2, Materiál: LIGNOPOR; Object Layer Attributes #2, Allright_Stavebni_dil_ID: 1354Ven0000001553; Object Layer Attributes #2, Jednotka: m2; Object Layer Attributes #2, Název_objektu: Věnec
 | Půdorys 1.PP | ZELEZOBETONOVÁ KCE 0.2 m, LIGNOPOR 0.025 m | 1 |  |  | 1354HWa0000001587 | m3 | Celá stěna | Stávající | Betonářské práce | ZELEZOBETONOVÁ KCE |  | 1354Ven0000001588 | m2 | Věnec |  | 0.225 | 0.9 | 0.9 | 0.193 | 0 | 0.193 | 0.77 | 0.25 | NEMSOK - Object Layer Attributes #2, 2D interakce: yes; Object Layer Attributes #2, Status: Stávající; Object Layer Attributes #2, Práce: Zateplovací systémy; Object Layer Attributes #2, Materiál: LIGNOPOR; Object Layer Attributes #2, Allright_Stavebni_dil_ID: 1354Ven0000001589; Object Layer Attributes #2, Jednotka: m2; Object Layer Attributes #2, Název_objektu: Věnec
 | Půdorys 1.PP | ZELEZOBETONOVÁ KCE 0.25 m, LIGNOPOR 0.025 m | 1 |  |  | 1354HWa0000001612 | m3 | Celá stěna | Stávající | Betonářské práce | ZELEZOBETONOVÁ KCE |  | 1354Ven0000001613 | m2 | Věnec |  | 0.275 | 0.33 | 0.33 | 0.091 | 0 | 0.091 | 0.363 | 0.25 | NEMSOK - Object Layer Attributes #2, 2D interakce: yes; Object Layer Attributes #2, Status: Stávající; Object Layer Attributes #2, Práce: Zateplovací systémy; Object Layer Attributes #2, Materiál: LIGNOPOR; Object Layer Attributes #2, Allright_Stavebni_dil_ID: 1354Ven0000001614; Object Layer Attributes #2, Jednotka: m2; Object Layer Attributes #2, Název_objektu: Věnec
 | Půdorys 1.PP | ZELEZOBETONOVÁ KCE 0.2 m, LIGNOPOR 0.025 m | 1 |  |  | 1354HWa0000001641 | m3 | Celá stěna | Stávající | Betonářské práce | ZELEZOBETONOVÁ KCE |  | 1354Ven0000001642 | m2 | Věnec |  | 0.225 | 4.391 | 4.391 | 0.974 | 0 | 0.974 | 3.897 | 0.25 | NEMSOK - Object Layer Attributes #2, 2D interakce: yes; Object Layer Attributes #2, Status: Stávající; Object Layer Attributes #2, Práce: Zateplovací systémy; Object Layer Attributes #2, Materiál: LIGNOPOR; Object Layer Attributes #2, Allright_Stavebni_dil_ID: 1354Ven0000001643; Object Layer Attributes #2, Jednotka: m2; Object Layer Attributes #2, Název_objektu: Věnec
 | Půdorys 1.PP | ZELEZOBETONOVÁ KCE 0.25 m, LIGNOPOR 0.025 m | 1 |  |  | 1354HWa0000001662 | m3 | Celá stěna | Stávající | Betonářské práce | ZELEZOBETONOVÁ KCE |  | 1354Ven0000001663 | m2 | Věnec |  | 0.275 | 0.33 | 0.33 | 0.091 | 0 | 0.091 | 0.363 | 0.25 | NEMSOK - Object Layer Attributes #2, 2D interakce: yes; Object Layer Attributes #2, Status: Stávající; Object Layer Attributes #2, Práce: Zateplovací systémy; Object Layer Attributes #2, Materiál: LIGNOPOR; Object Layer Attributes #2, Allright_Stavebni_dil_ID: 1354Ven0000001664; Object Layer Attributes #2, Jednotka: m2; Object Layer Attributes #2, Název_objektu: Věnec
 | Půdorys 1.PP | ZELEZOBETONOVÁ KCE 0.2 m, LIGNOPOR 0.025 m | 1 |  |  | 1354HWa0000001685 | m3 | Celá stěna | Stávající | Betonářské práce | ZELEZOBETONOVÁ KCE |  | 1354Ven0000001686 | m2 | Věnec |  | 0.225 | 2.395 | 2.395 | 0.539 | 0 | 0.539 | 2.156 | 0.25 | NEMSOK - Object Layer Attributes #2, 2D interakce: yes; Object Layer Attributes #2, Status: Stávající; Object Layer Attributes #2, Práce: Zateplovací systémy; Object Layer Attributes #2, Materiál: LIGNOPOR; Object Layer Attributes #2, Allright_Stavebni_dil_ID: 1354Ven0000001687; Object Layer Attributes #2, Jednotka: m2; Object Layer Attributes #2, Název_objektu: Věnec
 | Půdorys 1.PP | ZELEZOBETONOVÁ KCE 0.25 m, LIGNOPOR 0.025 m | 1 |  |  | 1354HWa0000001718 | m3 | Celá stěna | Stávající | Betonářské práce | ZELEZOBETONOVÁ KCE |  | 1354Ven0000001719 | m2 | Věnec |  | 0.275 | 0.45 | 0.45 | 0.121 | 0 | 0.121 | 0.483 | 0.25 | NEMSOK - Object Layer Attributes #2, 2D interakce: yes; Object Layer Attributes #2, Status: Stávající; Object Layer Attributes #2, Práce: Zateplovací systémy; Object Layer Attributes #2, Materiál: LIGNOPOR; Object Layer Attributes #2, Allright_Stavebni_dil_ID: 1354Ven0000001720; Object Layer Attributes #2, Jednotka: m2; Object Layer Attributes #2, Název_objektu: Věnec
 | Půdorys 1.PP | ZELEZOBETONOVÁ KCE 0.675 m, LIGNOPOR 0.025 m | 1 |  |  | 1354HWa0000001747 | m3 | Celá stěna | Stávající | Betonářské práce | ZELEZOBETONOVÁ KCE |  | 1354Ven0000001748 | m2 | Věnec |  | 0.7 | 0.75 | 0.75 | 0.525 | 0 | 0.525 | 2.1 | 0.25 | NEMSOK - Object Layer Attributes #2, 2D interakce: yes; Object Layer Attributes #2, Status: Stávající; Object Layer Attributes #2, Práce: Zateplovací systémy; Object Layer Attributes #2, Materiál: LIGNOPOR; Object Layer Attributes #2, Allright_Stavebni_dil_ID: 1354Ven0000001749; Object Layer Attributes #2, Jednotka: m2; Object Layer Attributes #2, Název_objektu: Věnec
 | Půdorys 1.PP | ZELEZOBETONOVÁ KCE 0.2 m, LIGNOPOR 0.025 m | 1 |  |  | 1354HWa0000001847 | m3 | Celá stěna | Stávající | Betonářské práce | ZELEZOBETONOVÁ KCE |  | 1354Ven0000001848 | m2 | Věnec |  | 0.225 | 4.536 | 4.536 | 1.006 | 0 | 1.006 | 4.024 | 0.25 | NEMSOK - Object Layer Attributes #2, 2D interakce: yes; Object Layer Attributes #2, Status: Stávající; Object Layer Attributes #2, Práce: Zateplovací systémy; Object Layer Attributes #2, Materiál: LIGNOPOR; Object Layer Attributes #2, Allright_Stavebni_dil_ID: 1354Ven0000001849; Object Layer Attributes #2, Jednotka: m2; Object Layer Attributes #2, Název_objektu: Věnec
 | Půdorys 1.PP | ZELEZOBETONOVÁ KCE 0.45 m, LIGNOPOR 0.025 m | 1 |  |  | 1354HWa0000001774 | m3 | Celá stěna | Stávající | Betonářské práce | ZELEZOBETONOVÁ KCE |  | 1354Ven0000001775 | m2 | Věnec |  | 0.475 | 2.069 | 2.069 | 0.929 | 0 | 0.929 | 3.717 | 0.25 | NEMSOK - Object Layer Attributes #2, 2D interakce: yes; Object Layer Attributes #2, Status: Stávající; Object Layer Attributes #2, Práce: Zateplovací systémy; Object Layer Attributes #2, Materiál: LIGNOPOR; Object Layer Attributes #2, Allright_Stavebni_dil_ID: 1354Ven0000001776; Object Layer Attributes #2, Jednotka: m2; Object Layer Attributes #2, Název_objektu: Věnec
 | Půdorys 1.PP | ZELEZOBETONOVÁ KCE 0.2 m, LIGNOPOR 0.025 m | 1 |  |  | 1354HWa0000001797 | m3 | Celá stěna | Stávající | Betonářské práce | ZELEZOBETONOVÁ KCE |  | 1354Ven0000001798 | m2 | Věnec |  | 0.225 | 0.155 | 0.155 | 0.035 | 0 | 0.035 | 0.14 | 0.25 | NEMSOK - Object Layer Attributes #2, 2D interakce: yes; Object Layer Attributes #2, Status: Stávající; Object Layer Attributes #2, Práce: Zateplovací systémy; Object Layer Attributes #2, Materiál: LIGNOPOR; Object Layer Attributes #2, Allright_Stavebni_dil_ID: 1354Ven0000001799; Object Layer Attributes #2, Jednotka: m2; Object Layer Attributes #2, Název_objektu: Věnec
 | Půdorys 1.PP | ZELEZOBETONOVÁ KCE 0.32 m, LIGNOPOR 0.025 m | 1 |  |  | 1354HWa0000001824 | m3 | Celá stěna | Stávající | Betonářské práce | ZELEZOBETONOVÁ KCE |  | 1354Ven0000001825 | m2 | Věnec |  | 0.345 | 4.006 | 4.006 | 1.364 | 0 | 1.364 | 5.457 | 0.25 | NEMSOK - Object Layer Attributes #2, 2D interakce: yes; Object Layer Attributes #2, Status: Stávající; Object Layer Attributes #2, Práce: Zateplovací systémy; Object Layer Attributes #2, Materiál: LIGNOPOR; Object Layer Attributes #2, Allright_Stavebni_dil_ID: 1354Ven0000001826; Object Layer Attributes #2, Jednotka: m2; Object Layer Attributes #2, Název_objektu: Věnec
AKUSTICKÝ OBKLAD | Půdorys 1.PP | AKUSTICKÝ OBKLAD 0.05 m | 1 | AKUSTICKÝ OBKLAD |  | 1364HWa0798523322 | m3 | Celá stěna | Nový | Suché stavební práce | AKUSTICKÝ OBKLAD | no | 1364Stě0798523323 | m3 | Stěna |  | 0.05 | 3.171 | 3.171 | 0.159 | 1.075 | 0.159 | 0.054 | 2.95 | NEMSOK - Object Layer Attributes #1, Kód prvku: AI02.02.0002; Object Layer Attributes #1, Požární odolnost: A2-s1; Object Layer Attributes #1, Systém kotvení: Mechanicky kotvený
AKUSTICKÝ OBKLAD | Půdorys 1.PP | AKUSTICKÝ OBKLAD 0.05 m | 1 | AKUSTICKÝ OBKLAD |  | 1364HWa0798523333 | m3 | Celá stěna | Nový | Suché stavební práce | AKUSTICKÝ OBKLAD | no | 1364Stě0798523334 | m3 | Stěna |  | 0.05 | 1.549 | 1.549 | 0.077 | 0.525 | 0.077 | 0.026 | 2.95 | NEMSOK - Object Layer Attributes #1, Kód prvku: AI02.02.0003; Object Layer Attributes #1, Požární odolnost: A2-s1; Object Layer Attributes #1, Systém kotvení: Mechanicky kotvený
AKUSTICKÝ OBKLAD | Půdorys 1.PP | AKUSTICKÝ OBKLAD 0.05 m | 1 | AKUSTICKÝ OBKLAD |  | 1364HWa0798523345 | m3 | Celá stěna | Nový | Suché stavební práce | AKUSTICKÝ OBKLAD | no | 1364Stě0798523346 | m3 | Stěna |  | 0.05 | 13.644 | 13.374 | 0.682 | 4.625 | 0.669 | 0.231 | 2.95 | NEMSOK - Object Layer Attributes #1, Kód prvku: AI02.02.0004; Object Layer Attributes #1, Požární odolnost: A2-s1; Object Layer Attributes #1, Systém kotvení: Mechanicky kotvený
AKUSTICKÝ OBKLAD | Půdorys 1.PP | AKUSTICKÝ OBKLAD 0.05 m | 1 | AKUSTICKÝ OBKLAD |  | 1364HWa0798523356 | m3 | Celá stěna | Nový | Suché stavební práce | AKUSTICKÝ OBKLAD | no | 1364Stě0798523357 | m3 | Stěna |  | 0.05 | 1.475 | 1.475 | 0.074 | 0.5 | 0.074 | 0.025 | 2.95 | NEMSOK - Object Layer Attributes #1, Kód prvku: AI02.02.0005; Object Layer Attributes #1, Požární odolnost: A2-s1; Object Layer Attributes #1, Systém kotvení: Mechanicky kotvený
AKUSTICKÝ OBKLAD | Půdorys 1.PP | AKUSTICKÝ OBKLAD 0.05 m | 1 | AKUSTICKÝ OBKLAD |  | 1364HWa0798523402 | m3 | Celá stěna | Nový | Suché stavební práce | AKUSTICKÝ OBKLAD | no | 1364Stě0798523403 | m3 | Stěna |  | 0.05 | 4.277 | 1.764 | 0.214 | 1.45 | 0.088 | 0.073 | 2.95 | NEMSOK - Object Layer Attributes #1, Kód prvku: AI02.02.0006; Object Layer Attributes #1, Požární odolnost: A2-s1; Object Layer Attributes #1, Systém kotvení: Mechanicky kotvený
AKUSTICKÝ OBKLAD | Půdorys 1.PP | AKUSTICKÝ OBKLAD 0.05 m |  | AKUSTICKÝ OBKLAD |  | 1364HWa0798523413 | m3 | Celá stěna | Nový | Suché stavební práce | AKUSTICKÝ OBKLAD | no | 1364Stě0798523414 | m3 | Stěna |  | 0.05 | 9.588 | 7.376 | 0.479 | 3.25 | 0.369 | 0.162 | 2.95 | NEMSOK - Object Layer Attributes #1, Kód prvku: AI02.02.0007; Object Layer Attributes #1, Požární odolnost: A2-s1; Object Layer Attributes #1, Systém kotvení: Mechanicky kotvený
AKUSTICKÝ OBKLAD | Půdorys 1.PP | AKUSTICKÝ OBKLAD 0.05 m | 1 | AKUSTICKÝ OBKLAD |  | 1364HWa0798523424 | m3 | Celá stěna | Nový | Suché stavební práce | AKUSTICKÝ OBKLAD | no | 1364Stě0798523425 | m3 | Stěna |  | 0.05 | 1.475 | 1.475 | 0.074 | 0.5 | 0.074 | 0.025 | 2.95 | NEMSOK - Object Layer Attributes #1, Kód prvku: AI02.02.0008; Object Layer Attributes #1, Požární odolnost: A2-s1; Object Layer Attributes #1, Systém kotvení: Mechanicky kotvený
AKUSTICKÝ OBKLAD | Půdorys 1.PP | AKUSTICKÝ OBKLAD 0.05 m | 1 | AKUSTICKÝ OBKLAD |  | 1364HWa0798523436 | m3 | Celá stěna | Nový | Suché stavební práce | AKUSTICKÝ OBKLAD | no | 1364Stě0798523437 | m3 | Stěna |  | 0.05 | 8.26 | 8.26 | 0.413 | 2.8 | 0.413 | 0.14 | 2.95 | NEMSOK - Object Layer Attributes #1, Kód prvku: AI02.02.0009; Object Layer Attributes #1, Požární odolnost: A2-s1; Object Layer Attributes #1, Systém kotvení: Mechanicky kotvený
AKUSTICKÝ OBKLAD | Půdorys 1.PP | AKUSTICKÝ OBKLAD 0.05 m | 1 | AKUSTICKÝ OBKLAD |  | 1364HWa0798523447 | m3 | Celá stěna | Nový | Suché stavební práce | AKUSTICKÝ OBKLAD | no | 1364Stě0798523448 | m3 | Stěna |  | 0.05 | 1.549 | 1.549 | 0.077 | 0.525 | 0.077 | 0.026 | 2.95 | NEMSOK - Object Layer Attributes #1, Kód prvku: AI02.02.0010; Object Layer Attributes #1, Požární odolnost: A2-s1; Object Layer Attributes #1, Systém kotvení: Mechanicky kotvený
AKUSTICKÝ OBKLAD | Půdorys 1.PP | AKUSTICKÝ OBKLAD 0.05 m | 1 | AKUSTICKÝ OBKLAD |  | 1364HWa0798523458 | m3 | Celá stěna | Nový | Suché stavební práce | AKUSTICKÝ OBKLAD | no | 1364Stě0798523459 | m3 | Stěna |  | 0.05 | 2.139 | 2.139 | 0.107 | 0.725 | 0.107 | 0.036 | 2.95 | NEMSOK - Object Layer Attributes #1, Kód prvku: AI02.02.0011; Object Layer Attributes #1, Požární odolnost: A2-s1; Object Layer Attributes #1, Systém kotvení: Mechanicky kotvený
AKUSTICKÝ OBKLAD | Půdorys 1.PP | AKUSTICKÝ OBKLAD 0.05 m | 1 | AKUSTICKÝ OBKLAD |  | 1364HWa0798524705 | m3 | Celá stěna | Nový | Suché stavební práce | AKUSTICKÝ OBKLAD | no | 1364Stě0798524706 | m3 | Stěna |  | 0.05 | 10.643 | 10.643 | 0.532 | 3.67 | 0.532 | 0.183 | 2.9 | NEMSOK - Object Layer Attributes #1, Kód prvku: AI02.02.0012; Object Layer Attributes #1, Požární odolnost: A2-s1; Object Layer Attributes #1, Systém kotvení: Mechanicky kotvený
AKUSTICKÝ OBKLAD | Půdorys 1.PP | AKUSTICKÝ OBKLAD 0.05 m | 1 | AKUSTICKÝ OBKLAD |  | 1364HWa0798524721 | m3 | Celá stěna | Nový | Suché stavební práce | AKUSTICKÝ OBKLAD | no | 1364Stě0798524722 | m3 | Stěna |  | 0.05 | 9.918 | 9.869 | 0.496 | 3.42 | 0.493 | 0.171 | 2.9 | NEMSOK - Object Layer Attributes #1, Kód prvku: AI02.02.0013; Object Layer Attributes #1, Požární odolnost: A2-s1; Object Layer Attributes #1, Systém kotvení: Mechanicky kotvený
AKUSTICKÝ OBKLAD | Půdorys 1.PP | AKUSTICKÝ OBKLAD 0.05 m | 1 | AKUSTICKÝ OBKLAD |  | 1364HWa0798524767 | m3 | Celá stěna | Nový | Suché stavební práce | AKUSTICKÝ OBKLAD | no | 1364Stě0798524768 | m3 | Stěna |  | 0.05 | 15.34 | 13.29 | 0.767 | 5.2 | 0.665 | 0.26 | 2.95 | NEMSOK - Object Layer Attributes #1, Kód prvku: AI02.02.0015; Object Layer Attributes #1, Požární odolnost: A2-s1; Object Layer Attributes #1, Systém kotvení: Mechanicky kotvený
AKUSTICKÝ OBKLAD | Půdorys 1.PP | AKUSTICKÝ OBKLAD 0.05 m | 1 | AKUSTICKÝ OBKLAD |  | 1364HWa0798524780 | m3 | Celá stěna | Nový | Suché stavební práce | AKUSTICKÝ OBKLAD | no | 1364Stě0798524781 | m3 | Stěna |  | 0.05 | 5.162 | 5.163 | 0.258 | 1.75 | 0.258 | 0.088 | 2.95 | NEMSOK - Object Layer Attributes #1, Kód prvku: AI02.02.0016; Object Layer Attributes #1, Požární odolnost: A2-s1; Object Layer Attributes #1, Systém kotvení: Mechanicky kotvený
AKUSTICKÝ OBKLAD | Půdorys 1.PP | AKUSTICKÝ OBKLAD 0.05 m | 1 | AKUSTICKÝ OBKLAD |  | 1364HWa0798524796 | m3 | Celá stěna | Nový | Suché stavební práce | AKUSTICKÝ OBKLAD | no | 1364Stě0798524797 | m3 | Stěna |  | 0.05 | 10.768 | 10.653 | 0.538 | 3.65 | 0.533 | 0.182 | 2.95 | NEMSOK - Object Layer Attributes #1, Kód prvku: AI02.02.0017; Object Layer Attributes #1, Požární odolnost: A2-s1; Object Layer Attributes #1, Systém kotvení: Mechanicky kotvený
AKUSTICKÝ OBKLAD | Půdorys 1.PP | AKUSTICKÝ OBKLAD 0.05 m | 1 | AKUSTICKÝ OBKLAD |  | 1364HWa0798524808 | m3 | Celá stěna | Nový | Suché stavební práce | AKUSTICKÝ OBKLAD | no | 1364Stě0798524809 | m3 | Stěna |  | 0.05 | 1.401 | 1.401 | 0.07 | 0.475 | 0.07 | 0.024 | 2.95 | NEMSOK - Object Layer Attributes #1, Kód prvku: AI02.02.0018; Object Layer Attributes #1, Požární odolnost: A2-s1; Object Layer Attributes #1, Systém kotvení: Mechanicky kotvený
AKUSTICKÝ OBKLAD | Půdorys 1.PP | AKUSTICKÝ OBKLAD 0.05 m | 1 | AKUSTICKÝ OBKLAD |  | 1364HWa0798524819 | m3 | Celá stěna | Nový | Suché stavební práce | AKUSTICKÝ OBKLAD | no | 1364Stě0798524820 | m3 | Stěna |  | 0.05 | 1.918 | 1.918 | 0.096 | 0.65 | 0.096 | 0.032 | 2.95 | NEMSOK - Object Layer Attributes #1, Kód prvku: AI02.02.0019; Object Layer Attributes #1, Požární odolnost: A2-s1; Object Layer Attributes #1, Systém kotvení: Mechanicky kotvený
AKUSTICKÝ OBKLAD | Půdorys 1.PP | AKUSTICKÝ OBKLAD 0.05 m | 1 | AKUSTICKÝ OBKLAD |  | 1364HWa0798524831 | m3 | Celá stěna | Nový | Suché stavební práce | AKUSTICKÝ OBKLAD | no | 1364Stě0798524832 | m3 | Stěna |  | 0.05 | 1.401 | 1.401 | 0.07 | 0.475 | 0.07 | 0.024 | 2.95 | NEMSOK - Object Layer Attributes #1, Kód prvku: AI02.02.0020; Object Layer Attributes #1, Požární odolnost: A2-s1; Object Layer Attributes #1, Systém kotvení: Mechanicky kotvený
AKUSTICKÝ OBKLAD | Půdorys 1.PP | AKUSTICKÝ OBKLAD 0.05 m | 1 | AKUSTICKÝ OBKLAD |  | 1364HWa0798524848 | m3 | Celá stěna | Nový | Suché stavební práce | AKUSTICKÝ OBKLAD | no | 1364Stě0798524849 | m3 | Stěna |  | 0.05 | 2.507 | 2.508 | 0.125 | 0.85 | 0.125 | 0.043 | 2.95 | NEMSOK - Object Layer Attributes #1, Kód prvku: AI02.02.0021; Object Layer Attributes #1, Požární odolnost: A2-s1; Object Layer Attributes #1, Systém kotvení: Mechanicky kotvený
AKUSTICKÝ OBKLAD | Půdorys 1.PP | AKUSTICKÝ OBKLAD 0.05 m | 1 | AKUSTICKÝ OBKLAD |  | 1364HWa0798524860 | m3 | Celá stěna | Nový | Suché stavební práce | AKUSTICKÝ OBKLAD | no | 1364Stě0798524861 | m3 | Stěna |  | 0.05 | 5.015 | 2.056 | 0.251 | 1.7 | 0.103 | 0.085 | 2.95 | NEMSOK - Object Layer Attributes #1, Kód prvku: AI02.02.0022; Object Layer Attributes #1, Požární odolnost: A2-s1; Object Layer Attributes #1, Systém kotvení: Mechanicky kotvený
AKUSTICKÝ OBKLAD | Půdorys 1.PP | AKUSTICKÝ OBKLAD 0.05 m |  | AKUSTICKÝ OBKLAD |  | 1364HWa0798524871 | m3 | Celá stěna | Nový | Suché stavební práce | AKUSTICKÝ OBKLAD | no | 1364Stě0798524872 | m3 | Stěna |  | 0.05 | 14.558 | 10.249 | 0.728 | 5.02 | 0.512 | 0.251 | 2.9 | NEMSOK - Object Layer Attributes #1, Kód prvku: AI02.02.0023; Object Layer Attributes #1, Požární odolnost: A2-s1; Object Layer Attributes #1, Systém kotvení: Mechanicky kotvený
AKUSTICKÝ OBKLAD | Půdorys 1.PP | AKUSTICKÝ OBKLAD 0.05 m | 1 | AKUSTICKÝ OBKLAD |  | 1364HWa0798524888 | m3 | Celá stěna | Nový | Suché stavební práce | AKUSTICKÝ OBKLAD | no | 1364Stě0798524889 | m3 | Stěna |  | 0.05 | 14.5 | 14.42 | 0.725 | 5 | 0.721 | 0.25 | 2.9 | NEMSOK - Object Layer Attributes #1, Kód prvku: AI02.02.0024; Object Layer Attributes #1, Požární odolnost: A2-s1; Object Layer Attributes #1, Systém kotvení: Mechanicky kotvený
AKUSTICKÝ OBKLAD | Půdorys 1.PP | AKUSTICKÝ OBKLAD 0.05 m | 1 | AKUSTICKÝ OBKLAD |  | 1364HWa0798524900 | m3 | Celá stěna | Nový | Suché stavební práce | AKUSTICKÝ OBKLAD | no | 1364Stě0798524901 | m3 | Stěna |  | 0.05 | 18.85 | 18.81 | 0.942 | 6.5 | 0.941 | 0.325 | 2.9 | NEMSOK - Object Layer Attributes #1, Kód prvku: AI02.02.0025; Object Layer Attributes #1, Požární odolnost: A2-s1; Object Layer Attributes #1, Systém kotvení: Mechanicky kotvený
AKUSTICKÝ OBKLAD | Půdorys 1.PP | AKUSTICKÝ OBKLAD 0.05 m | 1 | AKUSTICKÝ OBKLAD |  | 1364HWa0798524913 | m3 | Celá stěna | Nový | Suché stavební práce | AKUSTICKÝ OBKLAD | no | 1364Stě0798524914 | m3 | Stěna |  | 0.05 | 3.19 | 2.49 | 0.16 | 1.1 | 0.125 | 0.055 | 2.9 | NEMSOK - Object Layer Attributes #1, Kód prvku: AI02.02.0026; Object Layer Attributes #1, Požární odolnost: A2-s1; Object Layer Attributes #1, Systém kotvení: Mechanicky kotvený
AKUSTICKÝ OBKLAD | Půdorys 1.PP | AKUSTICKÝ OBKLAD 0.05 m | 1 | AKUSTICKÝ OBKLAD |  | 1364HWa0798524924 | m3 | Celá stěna | Nový | Suché stavební práce | AKUSTICKÝ OBKLAD | no | 1364Stě0798524925 | m3 | Stěna |  | 0.05 | 23.635 | 23.635 | 1.182 | 8.15 | 1.182 | 0.407 | 2.9 | NEMSOK - Object Layer Attributes #1, Kód prvku: AI02.02.0027; Object Layer Attributes #1, Požární odolnost: A2-s1; Object Layer Attributes #1, Systém kotvení: Mechanicky kotvený
AKUSTICKÝ OBKLAD | Půdorys 1.PP | AKUSTICKÝ OBKLAD 0.05 m | 1 | AKUSTICKÝ OBKLAD |  | 1364HWa0798526056 | m3 | Celá stěna | Nový | Suché stavební práce | AKUSTICKÝ OBKLAD | no | 1364Stě0798526057 | m3 | Stěna |  | 0.05 | 0.738 | 0.738 | 0.037 | 0.25 | 0.037 | 0.012 | 2.95 | NEMSOK - Object Layer Attributes #1, Kód prvku: AI02.02.0028; Object Layer Attributes #1, Požární odolnost: A2-s1; Object Layer Attributes #1, Systém kotvení: Mechanicky kotvený
AKUSTICKÝ OBKLAD | Půdorys 1.PP | AKUSTICKÝ OBKLAD 0.05 m | 1 | AKUSTICKÝ OBKLAD |  | 1364HWa0798524733 | m3 | Celá stěna | Nový | Suché stavební práce | AKUSTICKÝ OBKLAD | no | 1364Stě0798524734 | m3 | Stěna |  | 0.05 | 28.478 | 25.547 | 1.424 | 9.82 | 1.277 | 0.491 | 2.9 | NEMSOK - Object Layer Attributes #1, Kód prvku: AI02.02.0014; Object Layer Attributes #1, Požární odolnost: A2-s1; Object Layer Attributes #1, Systém kotvení: Mechanicky kotvený
PERIMETR | Půdorys 1.PP | PERIMETR 0.2 m |  | PERIMETR | E | 1364HWa0798516000 | m3 | Celá stěna | Nový | Zateplovací systémy | PERIMETR | no | 1364Stě0798516001 | m3 | Stěna |  | 0.2 | 37.337 | 31.938 | 7.467 | 12.875 | 6.387 | 2.575 | 2.9 | NEMSOK - Object Layer Attributes #1, Kód prvku: TI02.02.0054; Object Layer Attributes #1, Požární odolnost: E; Object Layer Attributes #1, Součinitel prostupu tepla: 0.034; Object Layer Attributes #1, Součinitel difúzního odporu: 40 - 100; Object Layer Attributes #1, Způsob spojení vrstev: Lepený
PERIMETR | Půdorys 1.PP | PERIMETR 0.2 m |  | PERIMETR |  | 1364HWa0798515470 | m3 | Celá stěna | Nový | Zateplovací systémy | PERIMETR | no | 1364Stě0798515471 | m3 | Stěna |  | 0.2 | 24.48 | 21.78 | 4.896 | 7.65 | 4.356 | 1.53 | 3.2 | NEMSOK - Object Layer Attributes #1, Kód prvku: TI02.02.0053; Object Layer Attributes #1, Požární odolnost: E; Object Layer Attributes #1, Součinitel prostupu tepla: 0.034; Object Layer Attributes #1, Součinitel difúzního odporu: 40 - 100; Object Layer Attributes #1, Způsob spojení vrstev: Lepený
PERIMETR | Půdorys 1.PP | PERIMETR 0.05 m |  | PERIMETR |  | 1364HWa0798512738 | m3 | Celá stěna | Nový | Zateplovací systémy | PERIMETR | no | 1364Stě0798512739 | m3 | Stěna |  | 0.05 | 2.617 | 2.617 | 0.131 | 2.145 | 0.131 | 0.107 | 1.22 | NEMSOK - Object Layer Attributes #1, Kód prvku: TI02.02.0043; Object Layer Attributes #1, Požární odolnost: E; Object Layer Attributes #1, Součinitel prostupu tepla: 0.034; Object Layer Attributes #1, Součinitel difúzního odporu: 40 - 100; Object Layer Attributes #1, Způsob spojení vrstev: Lepený
PERIMETR | Půdorys 1.PP | PERIMETR 0.05 m |  | PERIMETR |  | 1364HWa0798512759 | m3 | Celá stěna | Nový | Zateplovací systémy | PERIMETR | no | 1364Stě0798512760 | m3 | Stěna |  | 0.05 | 4.026 | 4.026 | 0.201 | 3.3 | 0.201 | 0.165 | 1.22 | NEMSOK - Object Layer Attributes #1, Kód prvku: TI02.02.0044; Object Layer Attributes #1, Požární odolnost: E; Object Layer Attributes #1, Součinitel prostupu tepla: 0.034; Object Layer Attributes #1, Součinitel difúzního odporu: 40 - 100; Object Layer Attributes #1, Způsob spojení vrstev: Lepený
PERIMETR | Půdorys 1.PP | PERIMETR 0.05 m |  | PERIMETR |  | 1364HWa0798512725 | m3 | Celá stěna | Nový | Zateplovací systémy | PERIMETR | no | 1364Stě0798512726 | m3 | Stěna |  | 0.05 | 12.505 | 12.505 | 0.625 | 10.25 | 0.625 | 0.513 | 1.22 | NEMSOK - Object Layer Attributes #1, Kód prvku: TI02.02.0042; Object Layer Attributes #1, Požární odolnost: E; Object Layer Attributes #1, Součinitel prostupu tepla: 0.034; Object Layer Attributes #1, Součinitel difúzního odporu: 40 - 100; Object Layer Attributes #1, Způsob spojení vrstev: Lepený
PERIMETR | Půdorys 1.PP | PERIMETR 0.05 m |  | PERIMETR |  | 1364HWa0798512713 | m3 | Celá stěna | Nový | Zateplovací systémy | PERIMETR | no | 1364Stě0798512714 | m3 | Stěna |  | 0.05 | 0.555 | 0.555 | 0.028 | 0.455 | 0.028 | 0.023 | 1.22 | NEMSOK - Object Layer Attributes #1, Kód prvku: TI02.02.0041; Object Layer Attributes #1, Požární odolnost: E; Object Layer Attributes #1, Součinitel prostupu tepla: 0.034; Object Layer Attributes #1, Součinitel difúzního odporu: 40 - 100; Object Layer Attributes #1, Způsob spojení vrstev: Lepený
PERIMETR | Půdorys 1.PP | PERIMETR 0.22 m |  | PERIMETR |  | 1364HWa0798506637 | m3 | Celá stěna | Nový | Zateplovací systémy | PERIMETR | no | 1364Stě0798506638 | m3 | Stěna |  | 0.22 | 1.855 | 1.855 | 0.408 | 1.521 | 0.408 | 0.335 | 1.22 | NEMSOK - Object Layer Attributes #1, Kód prvku: TI02.02.0019; Object Layer Attributes #1, Požární odolnost: E; Object Layer Attributes #1, Součinitel prostupu tepla: 0.034; Object Layer Attributes #1, Součinitel difúzního odporu: 40 - 100; Object Layer Attributes #1, Způsob spojení vrstev: Lepený
PERIMETR | Půdorys 1.PP | PERIMETR 0.22 m |  | PERIMETR |  | 1364HWa0798506629 | m3 | Celá stěna | Nový | Zateplovací systémy | PERIMETR | no | 1364Stě0798506630 | m3 | Stěna |  | 0.22 | 1.671 | 1.671 | 0.368 | 3.213 | 0.368 | 0.707 | 0.52 | NEMSOK - Object Layer Attributes #1, Kód prvku: TI02.02.0018; Object Layer Attributes #1, Požární odolnost: E; Object Layer Attributes #1, Součinitel prostupu tepla: 0.034; Object Layer Attributes #1, Součinitel difúzního odporu: 40 - 100; Object Layer Attributes #1, Způsob spojení vrstev: Lepený
PERIMETR | Půdorys 1.PP | PERIMETR 0.22 m |  | PERIMETR |  | 1364HWa0798506617 | m3 | Celá stěna | Nový | Zateplovací systémy | PERIMETR | no | 1364Stě0798506618 | m3 | Stěna |  | 0.22 | 1.173 | 1.173 | 0.258 | 0.962 | 0.258 | 0.212 | 1.22 | NEMSOK - Object Layer Attributes #1, Kód prvku: TI02.02.0017; Object Layer Attributes #1, Požární odolnost: E; Object Layer Attributes #1, Součinitel prostupu tepla: 0.034; Object Layer Attributes #1, Součinitel difúzního odporu: 40 - 100; Object Layer Attributes #1, Způsob spojení vrstev: Lepený
PERIMETR | Půdorys 1.PP | PERIMETR 0.22 m |  | PERIMETR |  | 1364HWa0798506605 | m3 | Celá stěna | Nový | Zateplovací systémy | PERIMETR | no | 1364Stě0798506606 | m3 | Stěna |  | 0.22 | 5.331 | 5.331 | 1.173 | 4.37 | 1.173 | 0.961 | 1.22 | NEMSOK - Object Layer Attributes #1, Kód prvku: TI02.02.0016; Object Layer Attributes #1, Požární odolnost: E; Object Layer Attributes #1, Součinitel prostupu tepla: 0.034; Object Layer Attributes #1, Součinitel difúzního odporu: 40 - 100; Object Layer Attributes #1, Způsob spojení vrstev: Lepený
PERIMETR | Půdorys 1.PP | PERIMETR 0.22 m |  | PERIMETR |  | 1364HWa0798506597 | m3 | Celá stěna | Nový | Zateplovací systémy | PERIMETR | no | 1364Stě0798506598 | m3 | Stěna |  | 0.22 | 1.22 | 1.22 | 0.268 | 1 | 0.268 | 0.22 | 1.22 | NEMSOK - Object Layer Attributes #1, Kód prvku: TI02.02.0015; Object Layer Attributes #1, Požární odolnost: E; Object Layer Attributes #1, Součinitel prostupu tepla: 0.034; Object Layer Attributes #1, Součinitel difúzního odporu: 40 - 100; Object Layer Attributes #1, Způsob spojení vrstev: Lepený
PERIMETR | Půdorys 1.PP | PERIMETR 0.22 m |  | PERIMETR |  | 1364HWa0798506589 | m3 | Celá stěna | Nový | Zateplovací systémy | PERIMETR | no | 1364Stě0798506590 | m3 | Stěna |  | 0.22 | 1.671 | 1.671 | 0.368 | 3.213 | 0.368 | 0.707 | 0.52 | NEMSOK - Object Layer Attributes #1, Kód prvku: TI02.02.0014; Object Layer Attributes #1, Požární odolnost: E; Object Layer Attributes #1, Součinitel prostupu tepla: 0.034; Object Layer Attributes #1, Součinitel difúzního odporu: 40 - 100; Object Layer Attributes #1, Způsob spojení vrstev: Lepený
PERIMETR | Půdorys 1.PP | PERIMETR 0.22 m |  | PERIMETR |  | 1364HWa0798506578 | m3 | Celá stěna | Nový | Zateplovací systémy | PERIMETR | no | 1364Stě0798506579 | m3 | Stěna |  | 0.22 | 0.314 | 0.314 | 0.069 | 0.257 | 0.069 | 0.057 | 1.22 | NEMSOK - Object Layer Attributes #1, Kód prvku: TI02.02.0013; Object Layer Attributes #1, Požární odolnost: E; Object Layer Attributes #1, Součinitel prostupu tepla: 0.034; Object Layer Attributes #1, Součinitel difúzního odporu: 40 - 100; Object Layer Attributes #1, Způsob spojení vrstev: Lepený
PERIMETR | Půdorys 1.PP | PERIMETR 0.22 m |  | PERIMETR |  | 1364HWa0798506573 | m3 | Celá stěna | Nový | Zateplovací systémy | PERIMETR | no | 1364Stě0798506574 | m3 | Stěna |  | 0.22 | 8.204 | 8.205 | 1.805 | 6.725 | 1.805 | 1.479 | 1.22 | NEMSOK - Object Layer Attributes #1, Kód prvku: TI02.02.0012; Object Layer Attributes #1, Požární odolnost: E; Object Layer Attributes #1, Součinitel prostupu tepla: 0.034; Object Layer Attributes #1, Součinitel difúzního odporu: 40 - 100; Object Layer Attributes #1, Způsob spojení vrstev: Lepený
PERIMETR | Půdorys 1.PP | PERIMETR 0.05 m |  | PERIMETR |  | 1364HWa0798512788 | m3 | Celá stěna | Nový | Zateplovací systémy | PERIMETR | no | 1364Stě0798512789 | m3 | Stěna |  | 0.05 | 4.52 | 4.52 | 0.226 | 3.705 | 0.226 | 0.185 | 1.22 | NEMSOK - Object Layer Attributes #1, Kód prvku: TI02.02.0047; Object Layer Attributes #1, Požární odolnost: E; Object Layer Attributes #1, Součinitel prostupu tepla: 0.034; Object Layer Attributes #1, Součinitel difúzního odporu: 40 - 100; Object Layer Attributes #1, Způsob spojení vrstev: Lepený
PERIMETR | Půdorys 1.PP | PERIMETR 0.05 m |  | PERIMETR |  | 1364HWa0798512776 | m3 | Celá stěna | Nový | Zateplovací systémy | PERIMETR | no | 1364Stě0798512777 | m3 | Stěna |  | 0.05 | 1.586 | 1.586 | 0.079 | 1.3 | 0.079 | 0.065 | 1.22 | NEMSOK - Object Layer Attributes #1, Kód prvku: TI02.02.0046; Object Layer Attributes #1, Požární odolnost: E; Object Layer Attributes #1, Součinitel prostupu tepla: 0.034; Object Layer Attributes #1, Součinitel difúzního odporu: 40 - 100; Object Layer Attributes #1, Způsob spojení vrstev: Lepený
PERIMETR | Půdorys 1.PP | PERIMETR 0.05 m |  | PERIMETR |  | 1364HWa0798512771 | m3 | Celá stěna | Nový | Zateplovací systémy | PERIMETR | no | 1364Stě0798512772 | m3 | Stěna |  | 0.05 | 5.118 | 5.118 | 0.256 | 4.195 | 0.256 | 0.21 | 1.22 | NEMSOK - Object Layer Attributes #1, Kód prvku: TI02.02.0045; Object Layer Attributes #1, Požární odolnost: E; Object Layer Attributes #1, Součinitel prostupu tepla: 0.034; Object Layer Attributes #1, Součinitel difúzního odporu: 40 - 100; Object Layer Attributes #1, Způsob spojení vrstev: Lepený
PERIMETR | Půdorys 1.PP | PERIMETR 0.05 m |  | PERIMETR |  | 1364HWa0798512508 | m3 | Celá stěna | Nový | Zateplovací systémy | PERIMETR | no | 1364Stě0798512509 | m3 | Stěna |  | 0.05 | 2.545 | 2.545 | 0.127 | 2.545 | 0.127 | 0.127 | 1 | NEMSOK - Object Layer Attributes #1, Kód prvku: TI02.02.0032; Object Layer Attributes #1, Požární odolnost: E; Object Layer Attributes #1, Součinitel prostupu tepla: 0.034; Object Layer Attributes #1, Součinitel difúzního odporu: 40 - 100; Object Layer Attributes #1, Způsob spojení vrstev: Lepený
PERIMETR | Půdorys 1.PP | PERIMETR 0.05 m |  | PERIMETR |  | 1364HWa0798512515 | m3 | Celá stěna | Nový | Zateplovací systémy | PERIMETR | no | 1364Stě0798512516 | m3 | Stěna |  | 0.05 | 3.48 | 3.48 | 0.174 | 3.48 | 0.174 | 0.174 | 1 | NEMSOK - Object Layer Attributes #1, Kód prvku: TI02.02.0033; Object Layer Attributes #1, Požární odolnost: E; Object Layer Attributes #1, Součinitel prostupu tepla: 0.034; Object Layer Attributes #1, Součinitel difúzního odporu: 40 - 100; Object Layer Attributes #1, Způsob spojení vrstev: Lepený
PERIMETR | Půdorys 1.PP | PERIMETR 0.05 m |  | PERIMETR |  | 1364HWa0798512531 | m3 | Celá stěna | Nový | Zateplovací systémy | PERIMETR | no | 1364Stě0798512532 | m3 | Stěna |  | 0.05 | 0.5 | 0.5 | 0.025 | 0.5 | 0.025 | 0.025 | 1 | NEMSOK - Object Layer Attributes #1, Kód prvku: TI02.02.0034; Object Layer Attributes #1, Požární odolnost: E; Object Layer Attributes #1, Součinitel prostupu tepla: 0.034; Object Layer Attributes #1, Součinitel difúzního odporu: 40 - 100; Object Layer Attributes #1, Způsob spojení vrstev: Lepený
PERIMETR | Půdorys 1.PP | PERIMETR 0.05 m |  | PERIMETR |  | 1364HWa0798512544 | m3 | Celá stěna | Nový | Zateplovací systémy | PERIMETR | no | 1364Stě0798512545 | m3 | Stěna |  | 0.05 | 2.195 | 2.195 | 0.11 | 2.195 | 0.11 | 0.11 | 1 | NEMSOK - Object Layer Attributes #1, Kód prvku: TI02.02.0035; Object Layer Attributes #1, Požární odolnost: E; Object Layer Attributes #1, Součinitel prostupu tepla: 0.034; Object Layer Attributes #1, Součinitel difúzního odporu: 40 - 100; Object Layer Attributes #1, Způsob spojení vrstev: Lepený
PERIMETR | Půdorys 1.PP | PERIMETR 0.05 m |  | PERIMETR |  | 1364HWa0798512562 | m3 | Celá stěna | Nový | Zateplovací systémy | PERIMETR | no | 1364Stě0798512563 | m3 | Stěna |  | 0.05 | 0.445 | 0.445 | 0.022 | 0.445 | 0.022 | 0.022 | 1 | NEMSOK - Object Layer Attributes #1, Kód prvku: TI02.02.0036; Object Layer Attributes #1, Požární odolnost: E; Object Layer Attributes #1, Součinitel prostupu tepla: 0.034; Object Layer Attributes #1, Součinitel difúzního odporu: 40 - 100; Object Layer Attributes #1, Způsob spojení vrstev: Lepený
PERIMETR | Půdorys 1.PP | PERIMETR 0.05 m |  | PERIMETR |  | 1364HWa0798512583 | m3 | Celá stěna | Nový | Zateplovací systémy | PERIMETR | no | 1364Stě0798512584 | m3 | Stěna |  | 0.05 | 5.075 | 5.075 | 0.254 | 5.075 | 0.254 | 0.254 | 1 | NEMSOK - Object Layer Attributes #1, Kód prvku: TI02.02.0037; Object Layer Attributes #1, Požární odolnost: E; Object Layer Attributes #1, Součinitel prostupu tepla: 0.034; Object Layer Attributes #1, Součinitel difúzního odporu: 40 - 100; Object Layer Attributes #1, Způsob spojení vrstev: Lepený
PERIMETR | Půdorys 1.PP | PERIMETR 0.22 m |  | PERIMETR |  | 1364HWa0798495138 | m3 | Celá stěna | Nový | Zateplovací systémy | PERIMETR | no | 1364Stě0798495242 | m3 | Stěna |  | 0.22 | 14 | 14 | 3.08 | 11.475 | 3.08 | 2.525 | 1.22 | NEMSOK - Object Layer Attributes #1, Kód prvku: TI02.02.0001; Object Layer Attributes #1, Požární odolnost: E; Object Layer Attributes #1, Součinitel prostupu tepla: 0.034; Object Layer Attributes #1, Součinitel difúzního odporu: 40 - 100; Object Layer Attributes #1, Způsob spojení vrstev: Lepený
PERIMETR | Půdorys 1.PP | PERIMETR 0.22 m |  | PERIMETR |  | 1364HWa0798495126 | m3 | Celá stěna | Nový | Zateplovací systémy | PERIMETR | no | 1364Stě0798495692 | m3 | Stěna |  | 0.22 | 17.965 | 17.965 | 3.952 | 14.725 | 3.952 | 3.24 | 1.22 | NEMSOK - Object Layer Attributes #1, Kód prvku: TI02.02.0002; Object Layer Attributes #1, Požární odolnost: E; Object Layer Attributes #1, Součinitel prostupu tepla: 0.034; Object Layer Attributes #1, Součinitel difúzního odporu: 40 - 100; Object Layer Attributes #1, Způsob spojení vrstev: Lepený
PERIMETR | Půdorys 1.PP | PERIMETR 0.22 m |  | PERIMETR |  | 1364HWa0798507658 | m3 | Celá stěna | Nový | Zateplovací systémy | PERIMETR | no | 1364Stě0798507661 | m3 | Stěna |  | 0.22 | 1.2 | 1.2 | 0.264 | 0.5 | 0.264 | 0.11 | 2.4 | NEMSOK - Object Layer Attributes #1, Kód prvku: TI02.02.0023; Object Layer Attributes #1, Požární odolnost: E; Object Layer Attributes #1, Součinitel prostupu tepla: 0.034; Object Layer Attributes #1, Součinitel difúzního odporu: 40 - 100; Object Layer Attributes #1, Způsob spojení vrstev: Lepený
PERIMETR | Půdorys 1.PP | PERIMETR 0.22 m |  | PERIMETR |  | 1364HWa0798507662 | m3 | Celá stěna | Nový | Zateplovací systémy | PERIMETR | no | 1364Stě0798507665 | m3 | Stěna |  | 0.22 | 1.2 | 1.2 | 0.264 | 0.5 | 0.264 | 0.11 | 2.4 | NEMSOK - Object Layer Attributes #1, Kód prvku: TI02.02.0024; Object Layer Attributes #1, Požární odolnost: E; Object Layer Attributes #1, Součinitel prostupu tepla: 0.034; Object Layer Attributes #1, Součinitel difúzního odporu: 40 - 100; Object Layer Attributes #1, Způsob spojení vrstev: Lepený
PERIMETR | Půdorys 1.PP | PERIMETR 0.22 m |  | PERIMETR |  | 1364HWa0798498992 | m3 | Celá stěna | Nový | Zateplovací systémy | PERIMETR | no | 1364Stě0798498993 | m3 | Stěna |  | 0.22 | 10.626 | 10.579 | 2.338 | 3.22 | 2.327 | 0.708 | 3.3 | NEMSOK - Object Layer Attributes #1, Kód prvku: TI02.02.0004; Object Layer Attributes #1, Požární odolnost: E; Object Layer Attributes #1, Součinitel prostupu tepla: 0.034; Object Layer Attributes #1, Součinitel difúzního odporu: 40 - 100; Object Layer Attributes #1, Způsob spojení vrstev: Lepený
PERIMETR | Půdorys 1.PP | PERIMETR 0.05 m |  | PERIMETR |  | 1364HWa0798512421 | m3 | Celá stěna | Nový | Zateplovací systémy | PERIMETR | no | 1364Stě0798512422 | m3 | Stěna |  | 0.05 | 0.155 | 0.155 | 0.008 | 0.155 | 0.008 | 0.008 | 1 | NEMSOK - Object Layer Attributes #1, Kód prvku: TI02.02.0028; Object Layer Attributes #1, Požární odolnost: E; Object Layer Attributes #1, Součinitel prostupu tepla: 0.034; Object Layer Attributes #1, Součinitel difúzního odporu: 40 - 100; Object Layer Attributes #1, Způsob spojení vrstev: Lepený
PERIMETR | Půdorys 1.PP | PERIMETR 0.05 m |  | PERIMETR |  | 1364HWa0798512433 | m3 | Celá stěna | Nový | Zateplovací systémy | PERIMETR | no | 1364Stě0798512434 | m3 | Stěna |  | 0.05 | 1.3 | 1.3 | 0.065 | 1.3 | 0.065 | 0.065 | 1 | NEMSOK - Object Layer Attributes #1, Kód prvku: TI02.02.0029; Object Layer Attributes #1, Požární odolnost: E; Object Layer Attributes #1, Součinitel prostupu tepla: 0.034; Object Layer Attributes #1, Součinitel difúzního odporu: 40 - 100; Object Layer Attributes #1, Způsob spojení vrstev: Lepený
PERIMETR | Půdorys 1.PP | PERIMETR 0.07 m |  | PERIMETR |  | 1364HWa0798512446 | m3 | Celá stěna | Nový | Zateplovací systémy | PERIMETR | no | 1364Stě0798512447 | m3 | Stěna |  | 0.07 | 3.6 | 3.6 | 0.252 | 3.6 | 0.252 | 0.252 | 1 | NEMSOK - Object Layer Attributes #1, Kód prvku: TI02.02.0030; Object Layer Attributes #1, Požární odolnost: E; Object Layer Attributes #1, Součinitel prostupu tepla: 0.034; Object Layer Attributes #1, Součinitel difúzního odporu: 40 - 100; Object Layer Attributes #1, Způsob spojení vrstev: Lepený
PERIMETR | Půdorys 1.PP | PERIMETR 0.05 m |  | PERIMETR |  | 1364HWa0798512466 | m3 | Celá stěna | Nový | Zateplovací systémy | PERIMETR | no | 1364Stě0798512467 | m3 | Stěna |  | 0.05 | 0.205 | 0.205 | 0.01 | 0.205 | 0.01 | 0.01 | 1 | NEMSOK - Object Layer Attributes #1, Kód prvku: TI02.02.0031; Object Layer Attributes #1, Požární odolnost: E; Object Layer Attributes #1, Součinitel prostupu tepla: 0.034; Object Layer Attributes #1, Součinitel difúzního odporu: 40 - 100; Object Layer Attributes #1, Způsob spojení vrstev: Lepený
PERIMETR | Půdorys 1.PP | PERIMETR 0.17 m |  | PERIMETR |  | 1364HWa0798512621 | m3 | Celá stěna | Nový | Zateplovací systémy | PERIMETR | no | 1364Stě0798512622 | m3 | Stěna |  | 0.17 | 31.311 | 31.219 | 5.323 | 8.82 | 5.307 | 1.499 | 3.55 | NEMSOK - Object Layer Attributes #1, Kód prvku: TI02.02.0038; Object Layer Attributes #1, Požární odolnost: E; Object Layer Attributes #1, Součinitel prostupu tepla: 0.034; Object Layer Attributes #1, Součinitel difúzního odporu: 40 - 100; Object Layer Attributes #1, Způsob spojení vrstev: Lepený
PERIMETR | Půdorys 1.PP | PERIMETR 0.08 m |  | PERIMETR |  | 1364HWa0798512636 | m3 | Celá stěna | Nový | Zateplovací systémy | PERIMETR | no | 1364Stě0798512637 | m3 | Stěna |  | 0.08 | 2.767 | 2.768 | 0.221 | 1.35 | 0.221 | 0.108 | 2.05 | NEMSOK - Object Layer Attributes #1, Kód prvku: TI02.02.0040; Object Layer Attributes #1, Požární odolnost: E; Object Layer Attributes #1, Součinitel prostupu tepla: 0.034; Object Layer Attributes #1, Součinitel difúzního odporu: 40 - 100; Object Layer Attributes #1, Způsob spojení vrstev: Lepený
PERIMETR | Půdorys 1.PP | PERIMETR 0.25 m |  | PERIMETR |  | 1364HWa0798512629 | m3 | Celá stěna | Nový | Zateplovací systémy | PERIMETR | no | 1364Stě0798512630 | m3 | Stěna |  | 0.25 | 1.065 | 1.065 | 0.266 | 0.3 | 0.266 | 0.075 | 3.55 | NEMSOK - Object Layer Attributes #1, Kód prvku: TI02.02.0039; Object Layer Attributes #1, Požární odolnost: E; Object Layer Attributes #1, Součinitel prostupu tepla: 0.034; Object Layer Attributes #1, Součinitel difúzního odporu: 40 - 100; Object Layer Attributes #1, Způsob spojení vrstev: Lepený
PERIMETR | Půdorys 1.PP | PERIMETR 0.22 m |  | PERIMETR |  | 1364HWa0798499871 | m3 | Celá stěna | Nový | Zateplovací systémy | PERIMETR | no | 1364Stě0798499872 | m3 | Stěna |  | 0.22 | 13.466 | 13.466 | 2.963 | 3.72 | 2.963 | 0.818 | 3.62 | NEMSOK - Object Layer Attributes #1, Kód prvku: TI02.02.0008; Object Layer Attributes #1, Požární odolnost: E; Object Layer Attributes #1, Součinitel prostupu tepla: 0.034; Object Layer Attributes #1, Součinitel difúzního odporu: 40 - 100; Object Layer Attributes #1, Způsob spojení vrstev: Lepený
PERIMETR | Půdorys 1.PP | PERIMETR 0.22 m |  | PERIMETR |  | 1364HWa0798499877 | m3 | Celá stěna | Nový | Zateplovací systémy | PERIMETR | no | 1364Stě0798499878 | m3 | Stěna |  | 0.22 | 26.792 | 26.792 | 5.894 | 7.88 | 5.894 | 1.734 | 3.4 | NEMSOK - Object Layer Attributes #1, Kód prvku: TI02.02.0009; Object Layer Attributes #1, Požární odolnost: E; Object Layer Attributes #1, Součinitel prostupu tepla: 0.034; Object Layer Attributes #1, Součinitel difúzního odporu: 40 - 100; Object Layer Attributes #1, Způsob spojení vrstev: Lepený
PERIMETR | Půdorys 1.PP | PERIMETR 0.22 m |  | PERIMETR |  | 1364HWa0798499226 | m3 | Celá stěna | Nový | Zateplovací systémy | PERIMETR | no | 1364Stě0798499227 | m3 | Stěna |  | 0.22 | 23.978 | 23.978 | 5.275 | 7.266 | 5.275 | 1.599 | 3.3 | NEMSOK - Object Layer Attributes #1, Kód prvku: TI02.02.0006; Object Layer Attributes #1, Požární odolnost: E; Object Layer Attributes #1, Součinitel prostupu tepla: 0.034; Object Layer Attributes #1, Součinitel difúzního odporu: 40 - 100; Object Layer Attributes #1, Způsob spojení vrstev: Lepený
PERIMETR | Půdorys 1.PP | PERIMETR 0.22 m |  | PERIMETR |  | 1364HWa0798507650 | m3 | Celá stěna | Nový | Zateplovací systémy | PERIMETR | no | 1364Stě0798507653 | m3 | Stěna |  | 0.22 | 1.2 | 1.2 | 0.264 | 0.5 | 0.264 | 0.11 | 2.4 | NEMSOK - Object Layer Attributes #1, Kód prvku: TI02.02.0021; Object Layer Attributes #1, Požární odolnost: E; Object Layer Attributes #1, Součinitel prostupu tepla: 0.034; Object Layer Attributes #1, Součinitel difúzního odporu: 40 - 100; Object Layer Attributes #1, Způsob spojení vrstev: Lepený
PERIMETR | Půdorys 1.PP | PERIMETR 0.22 m |  | PERIMETR |  | 1364HWa0798499309 | m3 | Celá stěna | Nový | Zateplovací systémy | PERIMETR | no | 1364Stě0798499310 | m3 | Stěna |  | 0.22 | 7.689 | 7.689 | 1.692 | 2.33 | 1.692 | 0.513 | 3.3 | NEMSOK - Object Layer Attributes #1, Kód prvku: TI02.02.0007; Object Layer Attributes #1, Požární odolnost: E; Object Layer Attributes #1, Součinitel prostupu tepla: 0.034; Object Layer Attributes #1, Součinitel difúzního odporu: 40 - 100; Object Layer Attributes #1, Způsob spojení vrstev: Lepený
PERIMETR | Půdorys 1.PP | PERIMETR 0.22 m |  | PERIMETR |  | 1364HWa0798499218 | m3 | Celá stěna | Nový | Zateplovací systémy | PERIMETR | no | 1364Stě0798499219 | m3 | Stěna |  | 0.22 | 14.104 | 14.104 | 3.103 | 4.274 | 3.103 | 0.94 | 3.3 | NEMSOK - Object Layer Attributes #1, Kód prvku: TI02.02.0005; Object Layer Attributes #1, Požární odolnost: E; Object Layer Attributes #1, Součinitel prostupu tepla: 0.034; Object Layer Attributes #1, Součinitel difúzního odporu: 40 - 100; Object Layer Attributes #1, Způsob spojení vrstev: Lepený
PERIMETR | Půdorys 1.PP | PERIMETR 0.22 m |  | PERIMETR |  | 1364HWa0798507654 | m3 | Celá stěna | Nový | Zateplovací systémy | PERIMETR | no | 1364Stě0798507657 | m3 | Stěna |  | 0.22 | 1.2 | 1.2 | 0.264 | 0.5 | 0.264 | 0.11 | 2.4 | NEMSOK - Object Layer Attributes #1, Kód prvku: TI02.02.0022; Object Layer Attributes #1, Požární odolnost: E; Object Layer Attributes #1, Součinitel prostupu tepla: 0.034; Object Layer Attributes #1, Součinitel difúzního odporu: 40 - 100; Object Layer Attributes #1, Způsob spojení vrstev: Lepený
PERIMETR | Půdorys 1.PP | PERIMETR 0.22 m |  | PERIMETR |  | 1364HWa0798506420 | m3 | Celá stěna | Nový | Zateplovací systémy | PERIMETR | no | 1364Stě0798506421 | m3 | Stěna |  | 0.22 | 18.66 | 18.66 | 4.105 | 15.295 | 4.105 | 3.365 | 1.22 | NEMSOK - Object Layer Attributes #1, Kód prvku: TI02.02.0010; Object Layer Attributes #1, Požární odolnost: E; Object Layer Attributes #1, Součinitel prostupu tepla: 0.034; Object Layer Attributes #1, Součinitel difúzního odporu: 40 - 100; Object Layer Attributes #1, Způsob spojení vrstev: Lepený
PERIMETR | Půdorys 1.PP | PERIMETR 0.22 m |  | PERIMETR |  | 1364HWa0798506434 | m3 | Celá stěna | Nový | Zateplovací systémy | PERIMETR | no | 1364Stě0798506435 | m3 | Stěna |  | 0.22 | 18.324 | 18.324 | 4.031 | 15.02 | 4.031 | 3.304 | 1.22 | NEMSOK - Object Layer Attributes #1, Kód prvku: TI02.02.0011; Object Layer Attributes #1, Požární odolnost: E; Object Layer Attributes #1, Součinitel prostupu tepla: 0.034; Object Layer Attributes #1, Součinitel difúzního odporu: 40 - 100; Object Layer Attributes #1, Způsob spojení vrstev: Lepený
PERIMETR | Půdorys 1.PP | PERIMETR 0.05 m |  | PERIMETR |  | 1364HWa0798507672 | m3 | Celá stěna | Nový | Zateplovací systémy | PERIMETR | no | 1364Stě0798507674 | m3 | Stěna |  | 0.05 | 2.82 | 2.82 | 0.141 | 2.82 | 0.141 | 0.141 | 1 | NEMSOK - Object Layer Attributes #1, Kód prvku: TI02.02.0026; Object Layer Attributes #1, Požární odolnost: E; Object Layer Attributes #1, Součinitel prostupu tepla: 0.034; Object Layer Attributes #1, Součinitel difúzního odporu: 40 - 100; Object Layer Attributes #1, Způsob spojení vrstev: Lepený
PERIMETR | Půdorys 1.PP | PERIMETR 0.05 m |  | PERIMETR |  | 1364HWa0798507668 | m3 | Celá stěna | Nový | Zateplovací systémy | PERIMETR | no | 1364Stě0798507676 | m3 | Stěna |  | 0.05 | 1.3 | 1.3 | 0.065 | 1.3 | 0.065 | 0.065 | 1 | NEMSOK - Object Layer Attributes #1, Kód prvku: TI02.02.0027; Object Layer Attributes #1, Požární odolnost: E; Object Layer Attributes #1, Součinitel prostupu tepla: 0.034; Object Layer Attributes #1, Součinitel difúzního odporu: 40 - 100; Object Layer Attributes #1, Způsob spojení vrstev: Lepený
PERIMETR | Půdorys 1.PP | PERIMETR 0.05 m |  | PERIMETR |  | 1364HWa0798507666 | m3 | Celá stěna | Nový | Zateplovací systémy | PERIMETR | no | 1364Stě0798507670 | m3 | Stěna |  | 0.05 | 9.58 | 9.58 | 0.479 | 9.58 | 0.479 | 0.479 | 1 | NEMSOK - Object Layer Attributes #1, Kód prvku: TI02.02.0025; Object Layer Attributes #1, Požární odolnost: E; Object Layer Attributes #1, Součinitel prostupu tepla: 0.034; Object Layer Attributes #1, Součinitel difúzního odporu: 40 - 100; Object Layer Attributes #1, Způsob spojení vrstev: Lepený
PERIMETR | Půdorys 1.PP | PERIMETR 0.08 m |  | PERIMETR |  | 1364HWa0798512950 | m3 | Celá stěna | Nový | Zateplovací systémy | PERIMETR | no | 1364Stě0798512951 | m3 | Stěna |  | 0.08 | 4.315 | 4.315 | 0.345 | 2.105 | 0.345 | 0.168 | 2.05 | NEMSOK - Object Layer Attributes #1, Kód prvku: TI02.02.0049; Object Layer Attributes #1, Požární odolnost: E; Object Layer Attributes #1, Součinitel prostupu tepla: 0.034; Object Layer Attributes #1, Součinitel difúzního odporu: 40 - 100; Object Layer Attributes #1, Způsob spojení vrstev: Lepený
PERIMETR | Půdorys 1.PP | PERIMETR 0.05 m |  | PERIMETR |  | 1364HWa0798512984 | m3 | Celá stěna | Nový | Zateplovací systémy | PERIMETR | no | 1364Stě0798512985 | m3 | Stěna |  | 0.05 | 1.35 | 1.35 | 0.068 | 1.35 | 0.068 | 0.068 | 1 | NEMSOK - Object Layer Attributes #1, Kód prvku: TI02.02.0051; Object Layer Attributes #1, Požární odolnost: E; Object Layer Attributes #1, Součinitel prostupu tepla: 0.034; Object Layer Attributes #1, Součinitel difúzního odporu: 40 - 100; Object Layer Attributes #1, Způsob spojení vrstev: Lepený
PERIMETR | Půdorys 1.PP | PERIMETR 0.08 m |  | PERIMETR |  | 1364HWa0798512956 | m3 | Celá stěna | Nový | Zateplovací systémy | PERIMETR | no | 1364Stě0798512957 | m3 | Stěna |  | 0.08 | 2.665 | 2.665 | 0.213 | 1.3 | 0.213 | 0.104 | 2.05 | NEMSOK - Object Layer Attributes #1, Kód prvku: TI02.02.0050; Object Layer Attributes #1, Požární odolnost: E; Object Layer Attributes #1, Součinitel prostupu tepla: 0.034; Object Layer Attributes #1, Součinitel difúzního odporu: 40 - 100; Object Layer Attributes #1, Způsob spojení vrstev: Lepený
PERIMETR | Půdorys 1.PP | PERIMETR 0.05 m |  | PERIMETR |  | 1364HWa0798506853 | m3 | Celá stěna | Nový | Zateplovací systémy | PERIMETR | no | 1364Stě0798506854 | m3 | Stěna |  | 0.05 | 5.225 | 5.225 | 0.261 | 5.225 | 0.261 | 0.261 | 1 | NEMSOK - Object Layer Attributes #1, Kód prvku: TI02.02.0020; Object Layer Attributes #1, Požární odolnost: E; Object Layer Attributes #1, Součinitel prostupu tepla: 0.034; Object Layer Attributes #1, Součinitel difúzního odporu: 40 - 100; Object Layer Attributes #1, Způsob spojení vrstev: Lepený
PERIMETR | Půdorys 1.PP | PERIMETR 0.08 m |  | PERIMETR |  | 1364HWa0798512922 | m3 | Celá stěna | Nový | Zateplovací systémy | PERIMETR | no | 1364Stě0798512923 | m3 | Stěna |  | 0.08 | 5.935 | 5.935 | 0.475 | 2.895 | 0.475 | 0.232 | 2.05 | NEMSOK - Object Layer Attributes #1, Kód prvku: TI02.02.0048; Object Layer Attributes #1, Požární odolnost: E; Object Layer Attributes #1, Součinitel prostupu tepla: 0.034; Object Layer Attributes #1, Součinitel difúzního odporu: 40 - 100; Object Layer Attributes #1, Způsob spojení vrstev: Lepený
PERIMETR | Půdorys 1.PP | PERIMETR 0.08 m |  | PERIMETR |  | 1364HWa0798513035 | m3 | Celá stěna | Nový | Zateplovací systémy | PERIMETR | no | 1364Stě0798513036 | m3 | Stěna |  | 0.08 | 0.102 | 0.103 | 0.008 | 0.05 | 0.008 | 0.004 | 2.05 | NEMSOK - Object Layer Attributes #1, Kód prvku: TI02.02.0052; Object Layer Attributes #1, Požární odolnost: E; Object Layer Attributes #1, Součinitel prostupu tepla: 0.034; Object Layer Attributes #1, Součinitel difúzního odporu: 40 - 100; Object Layer Attributes #1, Způsob spojení vrstev: Lepený
AKUSTICKÝ OBKLAD | Půdorys 1.PP | AKUSTICKÝ OBKLAD 0.05 m |  | AKUSTICKÝ OBKLAD |  | 1364HWa0798523317 | m3 | Celá stěna | Nový | Suché stavební práce | AKUSTICKÝ OBKLAD | no | 1364Stě0798523318 | m3 | Stěna |  | 0.05 | 8.702 | 8.453 | 0.435 | 2.95 | 0.423 | 0.148 | 2.95 | NEMSOK - Object Layer Attributes #1, Kód prvku: AI02.02.0001; Object Layer Attributes #1, Požární odolnost: A2-s1; Object Layer Attributes #1, Systém kotvení: Mechanicky kotvený
ZELEZOBETONOVÁ KCE | Půdorys 1.PP | ZELEZOBETONOVÁ KCE 0.2 m |  | ZELEZOBETONOVÁ KCE | A | 1364HWa0798495146 | m3 | Celá stěna | Nový | Betonářské práce | ZELEZOBETONOVÁ KCE | no | 1364Stě0798495179 | m3 | Stěna | 0 | 0.2 | 1.42 | 1.42 | 0.284 | 1.495 | 0.284 | 0.299 | 0.95 | Pset_WallCommon - LoadBearing: yes; NEMSOK - Object Layer Attributes #1, Kód prvku: SN02.02.0013; Object Layer Attributes #1, Funkce: Ne; Object Layer Attributes #1, U-hodnota: 3.37; Object Layer Attributes #1, Podlaží: 1.PP; Object Layer Attributes #1, Požární odolnost: A; Statická funkce: Ano; Object Layer Attributes #1, Třída pevnosti ocele: B500B; Object Layer Attributes #1, Stupeň vyztužení: 150; Object Layer Attributes #1, Třída pevnosti betonu: C25/30-XC1; Object Layer Attributes #1, Krytí výztuže: 25mm; Object Layer Attributes #1, Statická funkce: Ne
ZELEZOBETONOVÁ KCE | Půdorys 1.PP | ZELEZOBETONOVÁ KCE 0.2 m |  | ZELEZOBETONOVÁ KCE | A | 1364HWa0798495148 | m3 | Celá stěna | Nový | Betonářské práce | ZELEZOBETONOVÁ KCE | no | 1364Stě0798495183 | m3 | Stěna | 0 | 0.2 | 1.42 | 1.42 | 0.284 | 1.495 | 0.284 | 0.299 | 0.95 | Pset_WallCommon - LoadBearing: yes; NEMSOK - Object Layer Attributes #1, Kód prvku: SN02.02.0015; Object Layer Attributes #1, Funkce: Ne; Object Layer Attributes #1, U-hodnota: 3.37; Object Layer Attributes #1, Podlaží: 1.PP; Object Layer Attributes #1, Požární odolnost: A; Statická funkce: Ano; Object Layer Attributes #1, Třída pevnosti ocele: B500B; Object Layer Attributes #1, Stupeň vyztužení: 150; Object Layer Attributes #1, Třída pevnosti betonu: C25/30-XC1; Object Layer Attributes #1, Krytí výztuže: 25mm; Object Layer Attributes #1, Statická funkce: Ne
ZELEZOBETONOVÁ KCE | Půdorys 1.PP | ZELEZOBETONOVÁ KCE 0.2 m |  | ZELEZOBETONOVÁ KCE | A | 1364HWa0798495150 | m3 | Celá stěna | Nový | Betonářské práce | ZELEZOBETONOVÁ KCE | no | 1364Stě0798495181 | m3 | Stěna | 0 | 0.2 | 1.425 | 1.425 | 0.285 | 1.5 | 0.285 | 0.3 | 0.95 | Pset_WallCommon - LoadBearing: yes; NEMSOK - Object Layer Attributes #1, Kód prvku: SN02.02.0014; Object Layer Attributes #1, Funkce: Ne; Object Layer Attributes #1, U-hodnota: 3.37; Object Layer Attributes #1, Podlaží: 1.PP; Object Layer Attributes #1, Požární odolnost: A; Statická funkce: Ano; Object Layer Attributes #1, Třída pevnosti ocele: B500B; Object Layer Attributes #1, Stupeň vyztužení: 150; Object Layer Attributes #1, Třída pevnosti betonu: C25/30-XC1; Object Layer Attributes #1, Krytí výztuže: 25mm; Object Layer Attributes #1, Statická funkce: Ne
ZELEZOBETONOVÁ KCE | Půdorys 1.PP | ZELEZOBETONOVÁ KCE 0.2 m, LIGNOPOR 0.025 m, PÓROBETONOVÉ ZDIVO 0.08 m | 1 | ZELEZOBETONOVÁ KCE | A | 1364HWa0798606564 | m3 | Celá stěna | Stávající | Betonářské práce | ZELEZOBETONOVÁ KCE |  | 1364Stě0798606565 | m3 | Stěna | 0 | 0.305 | 2.25 | 0 | 0.686 | 1.5 | 0 | 0.457 | 1.5 | NEMSOK - Object Layer Attributes #2, 2D interakce: yes; Object Layer Attributes #2, Status: Stávající; Object Layer Attributes #2, Práce: Zateplovací systémy; Object Layer Attributes #2, Materiál: LIGNOPOR; Object Layer Attributes #2, Allright_Stavebni_dil_ID: 1364Stě0798606566; Object Layer Attributes #2, Jednotka: m3; Object Layer Attributes #2, Název_objektu: Stěna; Object Layer Attributes #3, 2D interakce: yes; Object Layer Attributes #3, Status: Stávající; Object Layer Attributes #3, Práce: Zednické práce; Object Layer Attributes #3, Materiál: PÓROBETONOVÉ ZDIVO; Object Layer Attributes #3, Allright_Stavebni_dil_ID: 1364Stě0798606567; Object Layer Attributes #3, Jednotka: m3; Object Layer Attributes #3, Název_objektu: Stěna; Statická funkce: Ano; Pset_WallCommon - LoadBearing: yes
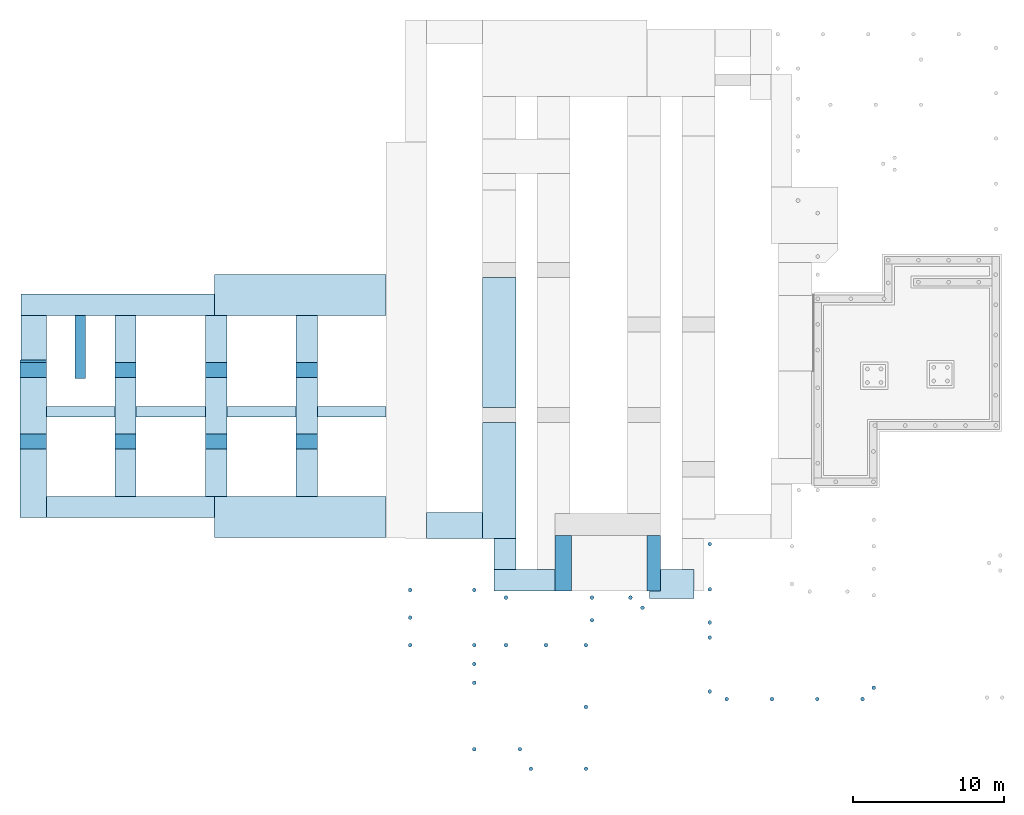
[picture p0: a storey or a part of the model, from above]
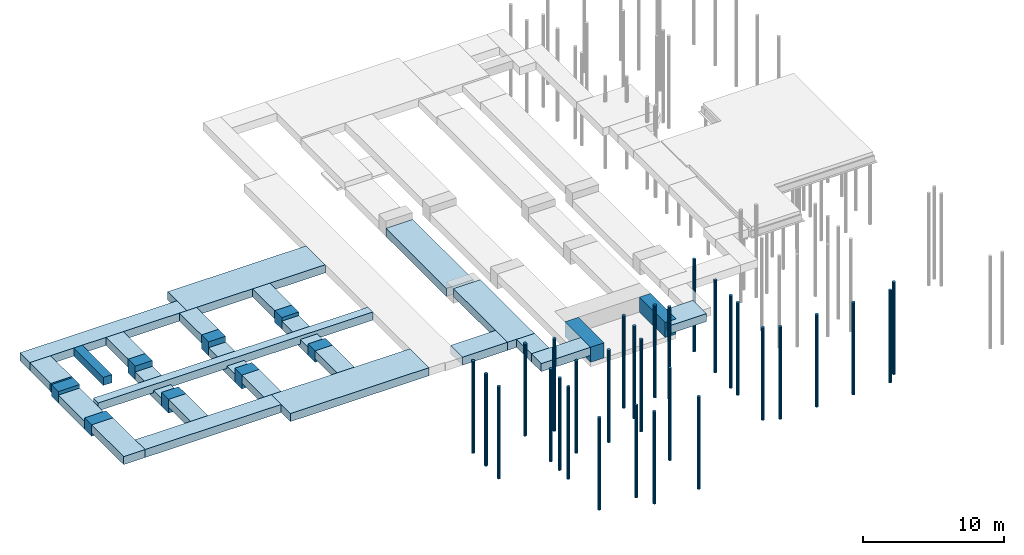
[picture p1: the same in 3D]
Properties of the parts of a building model (IFC4), part 28 of 45

# IfcWall (2385)
Name | In | Material | Faktor | Označení | Požární odolnost | Allright_Stavebni_dil_ID | Jednotka | Název_objektu | Object Layer Attributes #1, Status | Object Layer Attributes #1, Práce | Object Layer Attributes #1, Materiál | Object Layer Attributes #1, Staticky nosná konstrukce | Object Layer Attributes #1, Allright_Stavebni_dil_ID | Object Layer Attributes #1, Jednotka | Object Layer Attributes #1, Název_objektu | ThermalTransmittance (W/K/m2) | Width (m) | GrossSideArea (m2) | NetSideArea (m2) | GrossVolume (m3) | Length (m) | NetVolume (m3) | GrossFootprintArea (m2) | Height (m)
ZELEZOBETONOVÁ KCE | Půdorys 1.PP | ZELEZOBETONOVÁ KCE 0.2 m, LIGNOPOR 0.025 m, PÓROBETONOVÉ ZDIVO 0.08 m |  | ZELEZOBETONOVÁ KCE | A | 1364HWa0798606625 | m3 | Celá stěna | Stávající | Betonářské práce | ZELEZOBETONOVÁ KCE |  | 1364Stě0798606647 | m3 | Stěna | 0 | 0.305 | 2.25 | 0 | 0.686 | 1.5 | 0 | 0.458 | 1.5 | NEMSOK - Object Layer Attributes #2, 2D interakce: yes; Object Layer Attributes #2, Status: Stávající; Object Layer Attributes #2, Práce: Zateplovací systémy; Object Layer Attributes #2, Materiál: LIGNOPOR; Object Layer Attributes #2, Allright_Stavebni_dil_ID: 1364Stě0798606646; Object Layer Attributes #2, Jednotka: m3; Object Layer Attributes #2, Název_objektu: Stěna; Object Layer Attributes #3, 2D interakce: yes; Object Layer Attributes #3, Status: Stávající; Object Layer Attributes #3, Práce: Zednické práce; Object Layer Attributes #3, Materiál: PÓROBETONOVÉ ZDIVO; Object Layer Attributes #3, Allright_Stavebni_dil_ID: 1364Stě0798606645; Object Layer Attributes #3, Jednotka: m3; Object Layer Attributes #3, Název_objektu: Stěna; Statická funkce: Ano; Pset_WallCommon - LoadBearing: yes
ZELEZOBETONOVÁ KCE | Půdorys 1.PP | ZELEZOBETONOVÁ KCE 0.2 m, LIGNOPOR 0.025 m, PÓROBETONOVÉ ZDIVO 0.08 m |  | ZELEZOBETONOVÁ KCE | A | 1364HWa0798606676 | m3 | Celá stěna | Stávající | Betonářské práce | ZELEZOBETONOVÁ KCE |  | 1364Stě0798606678 | m3 | Stěna | 0 | 0.305 | 2.25 | 0 | 0.686 | 1.5 | 0 | 0.458 | 1.5 | NEMSOK - Object Layer Attributes #2, 2D interakce: yes; Object Layer Attributes #2, Status: Stávající; Object Layer Attributes #2, Práce: Zateplovací systémy; Object Layer Attributes #2, Materiál: LIGNOPOR; Object Layer Attributes #2, Allright_Stavebni_dil_ID: 1364Stě0798606679; Object Layer Attributes #2, Jednotka: m3; Object Layer Attributes #2, Název_objektu: Stěna; Object Layer Attributes #3, 2D interakce: yes; Object Layer Attributes #3, Status: Stávající; Object Layer Attributes #3, Práce: Zednické práce; Object Layer Attributes #3, Materiál: PÓROBETONOVÉ ZDIVO; Object Layer Attributes #3, Allright_Stavebni_dil_ID: 1364Stě0798606680; Object Layer Attributes #3, Jednotka: m3; Object Layer Attributes #3, Název_objektu: Stěna; Statická funkce: Ano; Pset_WallCommon - LoadBearing: yes
ZELEZOBETONOVÁ KCE | Půdorys 1.PP | ZELEZOBETONOVÁ KCE 0.2 m, LIGNOPOR 0.025 m, PÓROBETONOVÉ ZDIVO 0.08 m |  | ZELEZOBETONOVÁ KCE | A | 1364HWa0798606681 | m3 | Celá stěna | Stávající | Betonářské práce | ZELEZOBETONOVÁ KCE |  | 1364Stě0798606683 | m3 | Stěna | 0 | 0.305 | 2.25 | 0 | 0.686 | 1.5 | 0 | 0.458 | 1.5 | NEMSOK - Object Layer Attributes #2, 2D interakce: yes; Object Layer Attributes #2, Status: Stávající; Object Layer Attributes #2, Práce: Zateplovací systémy; Object Layer Attributes #2, Materiál: LIGNOPOR; Object Layer Attributes #2, Allright_Stavebni_dil_ID: 1364Stě0798606684; Object Layer Attributes #2, Jednotka: m3; Object Layer Attributes #2, Název_objektu: Stěna; Object Layer Attributes #3, 2D interakce: yes; Object Layer Attributes #3, Status: Stávající; Object Layer Attributes #3, Práce: Zednické práce; Object Layer Attributes #3, Materiál: PÓROBETONOVÉ ZDIVO; Object Layer Attributes #3, Allright_Stavebni_dil_ID: 1364Stě0798606685; Object Layer Attributes #3, Jednotka: m3; Object Layer Attributes #3, Název_objektu: Stěna; Statická funkce: Ano; Pset_WallCommon - LoadBearing: yes
ZELEZOBETONOVÁ KCE | Půdorys 1.PP | ZELEZOBETONOVÁ KCE 0.2 m, LIGNOPOR 0.025 m, PÓROBETONOVÉ ZDIVO 0.08 m |  | ZELEZOBETONOVÁ KCE | A | 1364HWa0798606939 | m3 | Celá stěna | Stávající | Betonářské práce | ZELEZOBETONOVÁ KCE |  | 1364Stě0798606954 | m3 | Stěna | 0 | 0.305 | 2.25 | 0 | 0.686 | 1.5 | 0 | 0.458 | 1.5 | NEMSOK - Object Layer Attributes #2, 2D interakce: yes; Object Layer Attributes #2, Status: Stávající; Object Layer Attributes #2, Práce: Zateplovací systémy; Object Layer Attributes #2, Materiál: LIGNOPOR; Object Layer Attributes #2, Allright_Stavebni_dil_ID: 1364Stě0798606955; Object Layer Attributes #2, Jednotka: m3; Object Layer Attributes #2, Název_objektu: Stěna; Object Layer Attributes #3, 2D interakce: yes; Object Layer Attributes #3, Status: Stávající; Object Layer Attributes #3, Práce: Zednické práce; Object Layer Attributes #3, Materiál: PÓROBETONOVÉ ZDIVO; Object Layer Attributes #3, Allright_Stavebni_dil_ID: 1364Stě0798606956; Object Layer Attributes #3, Jednotka: m3; Object Layer Attributes #3, Název_objektu: Stěna; Statická funkce: Ano; Pset_WallCommon - LoadBearing: yes
YTONG 125 | Půdorys 1.PP | YTONG 125 0.2 m |  | YTONG 125 | EI 180 | 1364HWa0000006678 | m3 | Celá stěna | Nový | Zednické práce | YTONG 125 | no | 1364Stě0000006679 | m3 | Stěna | 0.926 | 0.2 | 2.05 | 0 | 0.41 | 1 | 0 | 0.2 | 2.05 | Pset_WallCommon - AcousticRating: 39 dB; NEMSOK - Object Layer Attributes #1, Kód prvku: SN06.02.1001; Object Layer Attributes #1, Funkce: Ne; Object Layer Attributes #1, U-hodnota: 0.926; Object Layer Attributes #1, Podlaží: 1.PP; Object Layer Attributes #1, Neprůzvučnost: 37 dB; Object Layer Attributes #1, Požární odolnost: EI 180; Object Layer Attributes #1, Pevnost zdiva: 1,92 N/mm2; Object Layer Attributes #1, Funkce (venkovní): Ne; Object Layer Attributes #1, Statická funkce: Ne
YTONG 100 | Půdorys 1.PP | YTONG 100 0.1 m |  | YTONG 100 |  | 1364HWa0000008087 | m3 | Celá stěna | Nový | Zednické práce | YTONG 100 | no | 1364Stě0000008088 | m3 | Stěna |  | 0.1 | 0.686 | 0.686 | 0.069 | 0.225 | 0.069 | 0.022 | 3.05 | NEMSOK - Object Layer Attributes #1, Kód prvku: SN06.02.1002; Object Layer Attributes #1, Funkce: Ne; Object Layer Attributes #1, U-hodnota: 1.111; Object Layer Attributes #1, Podlaží: 1.PP; Object Layer Attributes #1, Neprůzvučnost: 35 dB; Object Layer Attributes #1, Požární odolnost: EI 120; Object Layer Attributes #1, Pevnost zdiva: 1,92 N/mm2; Object Layer Attributes #1, Funkce (venkovní): Ne; Object Layer Attributes #1, Statická funkce: Ne
YTONG 100 | Půdorys 1.PP | YTONG 100 0.1 m |  | YTONG 100 |  | 1364HWa0000008204 | m3 | Celá stěna | Nový | Zednické práce | YTONG 100 | no | 1364Stě0000008205 | m3 | Stěna |  | 0.1 | 1.983 | 1.983 | 0.198 | 0.65 | 0.198 | 0.065 | 3.05 | NEMSOK - Object Layer Attributes #1, Kód prvku: SN06.02.1003; Object Layer Attributes #1, Funkce: Ne; Object Layer Attributes #1, U-hodnota: 1.111; Object Layer Attributes #1, Podlaží: 1.PP; Object Layer Attributes #1, Neprůzvučnost: 35 dB; Object Layer Attributes #1, Požární odolnost: EI 120; Object Layer Attributes #1, Pevnost zdiva: 1,92 N/mm2; Object Layer Attributes #1, Funkce (venkovní): Ne; Object Layer Attributes #1, Statická funkce: Ne
SANITARNÍ PŘÍČKA | Půdorys 1.PP | layer 0.032 m |  | SANITARNÍ PŘÍČKA |  | 1364HWa0000010593 | Kus | I.SP1 | Nový | Suché stavební práce |  |  | 1364Stě0000010636 | m3 | Stěna |  | 0.032 | 1.665 | 0.259 | 0.053 | 0.9 | 0.008 | 0.029 | 1.85 | NEMSOK - Object Layer Attributes #1, Kód prvku: SN16.02.0003; Object Layer Attributes #1, Podlaží: 1.PP; Object Layer Attributes #1, Funkce (venkovní): Ne
YTONG 100 | Půdorys 1.PP | YTONG 100 0.1 m |  | YTONG 100 |  | 1364HWa0798473001 | m3 | Celá stěna | Nový | Zednické práce | YTONG 100 | no | 1364Stě0798473002 | m3 | Stěna |  | 0.1 | 0.686 | 0.686 | 0.069 | 0.225 | 0.069 | 0.022 | 3.05 | NEMSOK - Object Layer Attributes #1, Kód prvku: SN06.02.1004; Object Layer Attributes #1, Funkce: Ne; Object Layer Attributes #1, U-hodnota: 1.111; Object Layer Attributes #1, Podlaží: 1.PP; Object Layer Attributes #1, Neprůzvučnost: 35 dB; Object Layer Attributes #1, Požární odolnost: EI 120; Object Layer Attributes #1, Pevnost zdiva: 1,92 N/mm2; Object Layer Attributes #1, Funkce (venkovní): Ne; Object Layer Attributes #1, Statická funkce: Ne
STĚNA ANGLICKÉHO DVORKU | Půdorys 1.PP | POHLEDOVY BETON 0.08 m |  | STĚNA ANGLICKÉHO DVORKU | A | 1364HWa0798473471 | m3 | Celá stěna | Nový | Betonářské práce | POHLEDOVY BETON | no | 1364Stě0798473472 | m3 | I.AD1 | 0 | 0.08 | 2.43 | 2.43 | 0.194 | 1.08 | 0.194 | 0.086 | 2.25 | NEMSOK - Object Layer Attributes #1, Kód prvku: OV00.02.0001; Object Layer Attributes #1, Podlaží: 1.PP; Object Layer Attributes #1, Statická funkce: Ne
YTONG 100 | Půdorys 1.PP | YTONG 100 |  | YTONG 100 |  | 1364HWa0798473655 | m3 | Celá stěna | Nový | Zednické práce | YTONG 100 | no | 1364Stě0798473656 | m3 | Stěna |  | 0.1 | 5.871 | 3.44 | 0.587 | 1.925 | 0.344 | 0.193 | 3.05 | NEMSOK - Object Layer Attributes #1, Kód prvku: SN06.02.1006; Object Layer Attributes #1, Funkce: Ne; Object Layer Attributes #1, U-hodnota: 1.111; Object Layer Attributes #1, Podlaží: 1.PP; Object Layer Attributes #1, Neprůzvučnost: 35 dB; Object Layer Attributes #1, Požární odolnost: EI 120; Object Layer Attributes #1, Pevnost zdiva: 1,92 N/mm2; Object Layer Attributes #1, Funkce (venkovní): Ne; Object Layer Attributes #1, Statická funkce: Ne
SANITÁRNÍ PŘÍČKA | Půdorys 1.PP | layer 0.032 m |  | SANITÁRNÍ PŘÍČKA |  | 1364HWa0798477136 | m3 | I.SP2 | Nový | Suché stavební práce |  |  | 1364Stě0798477138 | m3 | Stěna |  | 0.032 | 2.22 | 2.22 | 0.071 | 1.2 | 0.071 | 0.038 | 1.85 | NEMSOK - Object Layer Attributes #1, Kód prvku: SN16.02.0002; Object Layer Attributes #1, Podlaží: 1.PP; Object Layer Attributes #1, Funkce (venkovní): Ne
SANITÁRNÍ PŘÍČKA | Půdorys 1.PP | layer 0.032 m |  | SANITÁRNÍ PŘÍČKA |  | 1364HWa0798477140 | m3 | I.SP2 | Nový | Suché stavební práce |  | no | 1364Stě0798477142 | m3 | Stěna |  | 0.032 | 2.22 | 2.22 | 0.071 | 1.2 | 0.071 | 0.038 | 1.85 | NEMSOK - Object Layer Attributes #1, Kód prvku: SN16.02.0001; Object Layer Attributes #1, Podlaží: 1.PP; Object Layer Attributes #1, Funkce (venkovní): Ne; Object Layer Attributes #1, Statická funkce: Ne
YTONG 250 | Půdorys 1.PP | YTONG 250 0.25 m |  | YTONG 250 |  | 1364HWa0798477464 | m3 | Celá stěna | Nový | Zednické práce | YTONG 250 | no | 1364Stě0798477466 | m3 | Stěna |  | 0.25 | 2.025 | 2.025 | 0.506 | 0.9 | 0.506 | 0.225 | 2.25 | NEMSOK - Object Layer Attributes #1, Kód prvku: SN06.02.0001; Object Layer Attributes #1, Funkce: Ne; Object Layer Attributes #1, U-hodnota: 0.429; Object Layer Attributes #1, Podlaží: 1.PP; Object Layer Attributes #1, Neprůzvučnost: 43 dB; Object Layer Attributes #1, Požární odolnost: REI 180; Object Layer Attributes #1, Pevnost zdiva: 2,32 N/mm2; Object Layer Attributes #1, Funkce (venkovní): Ne; Object Layer Attributes #1, Statická funkce: Ne
YTONG 250 | Půdorys 1.PP | YTONG 250 0.25 m |  | YTONG 250 | REI 180 | 1364HWa0798477470 | m3 | Celá stěna | Nový | Zednické práce | YTONG 250 | no | 1364Stě0798477472 | m3 | Stěna | 0.637 | 0.25 | 2.475 | 2.475 | 0.619 | 1.1 | 0.619 | 0.275 | 2.25 | Pset_WallCommon - AcousticRating: 47 dB; NEMSOK - Object Layer Attributes #1, Kód prvku: SN06.02.0002; Object Layer Attributes #1, Funkce: Ne; Object Layer Attributes #1, U-hodnota: 0.429; Object Layer Attributes #1, Podlaží: 1.PP; Object Layer Attributes #1, Neprůzvučnost: 43 dB; Object Layer Attributes #1, Požární odolnost: REI 180; Object Layer Attributes #1, Pevnost zdiva: 2,32 N/mm2; Object Layer Attributes #1, Funkce (venkovní): Ne; Object Layer Attributes #1, Statická funkce: Ne
YTONG 250 | Půdorys 1.PP | YTONG 250 0.25 m |  | YTONG 250 | REI 180 | 1364HWa0798477479 | m3 | Celá stěna | Nový | Zednické práce | YTONG 250 | no | 1364Stě0798477481 | m3 | Stěna | 0.637 | 0.25 | 2.475 | 2.052 | 0.619 | 1.1 | 0.545 | 0.275 | 2.25 | Pset_WallCommon - AcousticRating: 47 dB; NEMSOK - Object Layer Attributes #1, Kód prvku: SN06.02.0003; Object Layer Attributes #1, Funkce: Ne; Object Layer Attributes #1, U-hodnota: 0.429; Object Layer Attributes #1, Podlaží: 1.PP; Object Layer Attributes #1, Neprůzvučnost: 43 dB; Object Layer Attributes #1, Požární odolnost: REI 180; Object Layer Attributes #1, Pevnost zdiva: 2,32 N/mm2; Object Layer Attributes #1, Funkce (venkovní): Ne; Object Layer Attributes #1, Statická funkce: Ne
YTONG 100 | Půdorys 1.PP | YTONG 100 0.1 m |  | YTONG 100 |  | 1364HWa0798481859 | m3 | Celá stěna | Nový | Zednické práce | YTONG 100 | no | 1364Stě0798481860 | m3 | Stěna |  | 0.1 | 0.61 | 0.61 | 0.061 | 0.2 | 0.061 | 0.02 | 3.05 | NEMSOK - Object Layer Attributes #1, Kód prvku: SN06.02.1007; Object Layer Attributes #1, Funkce: Ne; Object Layer Attributes #1, U-hodnota: 1.111; Object Layer Attributes #1, Podlaží: 1.PP; Object Layer Attributes #1, Neprůzvučnost: 35 dB; Object Layer Attributes #1, Požární odolnost: EI 120; Object Layer Attributes #1, Pevnost zdiva: 1,92 N/mm2; Object Layer Attributes #1, Funkce (venkovní): Ne; Object Layer Attributes #1, Statická funkce: Ne
STĚNA ANGLICKÉHO DVORKU | Půdorys 1.PP | POHLEDOVY BETON 0.08 m |  | STĚNA ANGLICKÉHO DVORKU | A | 1364HWa0798482041 | m3 | Celá stěna | Nový | Betonářské práce | POHLEDOVY BETON | no | 1364Stě0798482042 | m3 | I.AD1 | 0 | 0.08 | 2.993 | 2.993 | 0.239 | 1.33 | 0.239 | 0.106 | 2.25 | NEMSOK - Object Layer Attributes #1, Kód prvku: OV00.02.0001; Object Layer Attributes #1, Podlaží: 1.PP; Object Layer Attributes #1, Statická funkce: Ne
STĚNA ANGLICKÉHO DVORKU | Půdorys 1.PP | POHLEDOVY BETON 0.08 m |  | STĚNA ANGLICKÉHO DVORKU | A | 1364HWa0798482052 | m3 | Celá stěna | Nový | Betonářské práce | POHLEDOVY BETON | no | 1364Stě0798482053 | m3 | I.AD1 | 0 | 0.08 | 2.25 | 2.25 | 0.18 | 1 | 0.18 | 0.08 | 2.25 | NEMSOK - Object Layer Attributes #1, Kód prvku: OV00.02.0001; Object Layer Attributes #1, Podlaží: 1.PP; Object Layer Attributes #1, Statická funkce: Ne
STĚNA ANGLICKÉHO DVORKU | Půdorys 1.PP | POHLEDOVY BETON 0.08 m |  | STĚNA ANGLICKÉHO DVORKU | A | 1364HWa0798482141 | m3 | I.AD2 | Nový | Betonářské práce | POHLEDOVY BETON | no | 1364Stě0798482145 | m3 | I.AD2 | 0 | 0.08 | 1.188 | 1.188 | 0.095 | 0.88 | 0.095 | 0.07 | 1.35 | NEMSOK - Object Layer Attributes #1, Kód prvku: OV00.02.0001; Object Layer Attributes #1, Podlaží: 1.PP; Object Layer Attributes #1, Statická funkce: Ne
STĚNA ANGLICKÉHO DVORKU | Půdorys 1.PP | POHLEDOVY BETON 0.08 m |  | STĚNA ANGLICKÉHO DVORKU | A | 1364HWa0798482144 | m3 | I.AD2 | Nový | Betonářské práce | POHLEDOVY BETON | no | 1364Stě0798482150 | m3 | I.AD2 | 0 | 0.08 | 2.875 | 2.876 | 0.23 | 2.13 | 0.23 | 0.17 | 1.35 | NEMSOK - Object Layer Attributes #1, Kód prvku: OV00.02.0001; Object Layer Attributes #1, Podlaží: 1.PP; Object Layer Attributes #1, Statická funkce: Ne
STĚNA ANGLICKÉHO DVORKU | Půdorys 1.PP | POHLEDOVY BETON 0.08 m |  | STĚNA ANGLICKÉHO DVORKU | A | 1364HWa0798482148 | m3 | I.AD2 | Nový | Betonářské práce | POHLEDOVY BETON | no | 1364Stě0798482151 | m3 | I.AD2 | 0 | 0.08 | 1.08 | 1.08 | 0.086 | 0.8 | 0.086 | 0.064 | 1.35 | NEMSOK - Object Layer Attributes #1, Kód prvku: OV00.02.0001; Object Layer Attributes #1, Podlaží: 1.PP; Object Layer Attributes #1, Statická funkce: Ne
STĚNA ANGLICKÉHO DVORKU | Půdorys 1.PP | POHLEDOVY BETON 0.08 m |  | STĚNA ANGLICKÉHO DVORKU | A | 1364HWa0798482208 | m3 | I.AD2 | Nový | Betonářské práce | POHLEDOVY BETON | no | 1364Stě0798482217 | m3 | I.AD2 | 0 | 0.08 | 1.08 | 1.08 | 0.086 | 0.8 | 0.086 | 0.064 | 1.35 | NEMSOK - Object Layer Attributes #1, Kód prvku: OV00.02.0001; Object Layer Attributes #1, Podlaží: 1.PP; Object Layer Attributes #1, Statická funkce: Ne
STĚNA ANGLICKÉHO DVORKU | Půdorys 1.PP | POHLEDOVY BETON 0.08 m |  | STĚNA ANGLICKÉHO DVORKU | A | 1364HWa0798482210 | m3 | I.AD2 | Nový | Betonářské práce | POHLEDOVY BETON | no | 1364Stě0798482216 | m3 | I.AD2 | 0 | 0.08 | 2.875 | 2.876 | 0.23 | 2.13 | 0.23 | 0.17 | 1.35 | NEMSOK - Object Layer Attributes #1, Kód prvku: OV00.02.0001; Object Layer Attributes #1, Podlaží: 1.PP; Object Layer Attributes #1, Statická funkce: Ne
STĚNA ANGLICKÉHO DVORKU | Půdorys 1.PP | POHLEDOVY BETON 0.08 m |  | STĚNA ANGLICKÉHO DVORKU | A | 1364HWa0798482212 | m3 | I.AD2 | Nový | Betonářské práce | POHLEDOVY BETON | no | 1364Stě0798482219 | m3 | I.AD2 | 0 | 0.08 | 1.188 | 1.188 | 0.095 | 0.88 | 0.095 | 0.07 | 1.35 | NEMSOK - Object Layer Attributes #1, Kód prvku: OV00.02.0001; Object Layer Attributes #1, Podlaží: 1.PP; Object Layer Attributes #1, Statická funkce: Ne
STĚNA ANGLICKÉHO DVORKU | Půdorys 1.PP | POHLEDOVY BETON 0.08 m |  | STĚNA ANGLICKÉHO DVORKU | A | 1364HWa0798482222 | Kus | I.AD2 | Nový | Betonářské práce | POHLEDOVY BETON | no | 1364Stě0798482231 | m3 | I.AD2 | 0 | 0.08 | 1.08 | 1.08 | 0.086 | 0.8 | 0.086 | 0.064 | 1.35 | NEMSOK - Object Layer Attributes #1, Kód prvku: OV00.02.0001; Object Layer Attributes #1, Podlaží: 1.PP; Object Layer Attributes #1, Statická funkce: Ne
STĚNA ANGLICKÉHO DVORKU | Půdorys 1.PP | POHLEDOVY BETON 0.08 m |  | STĚNA ANGLICKÉHO DVORKU | A | 1364HWa0798482224 | m3 | I.AD2 | Nový | Betonářské práce | POHLEDOVY BETON | no | 1364Stě0798482230 | m3 | I.AD2 | 0 | 0.08 | 2.875 | 2.876 | 0.23 | 2.13 | 0.23 | 0.17 | 1.35 | NEMSOK - Object Layer Attributes #1, Kód prvku: OV00.02.0001; Object Layer Attributes #1, Podlaží: 1.PP; Object Layer Attributes #1, Statická funkce: Ne
STĚNA ANGLICKÉHO DVORKU | Půdorys 1.PP | POHLEDOVY BETON 0.08 m |  | STĚNA ANGLICKÉHO DVORKU | A | 1364HWa0798482226 | m3 | I.AD2 | Nový | Betonářské práce | POHLEDOVY BETON | no | 1364Stě0798482233 | m3 | I.AD2 | 0 | 0.08 | 1.188 | 1.188 | 0.095 | 0.88 | 0.095 | 0.07 | 1.35 | NEMSOK - Object Layer Attributes #1, Kód prvku: OV00.02.0001; Object Layer Attributes #1, Podlaží: 1.PP; Object Layer Attributes #1, Statická funkce: Ne
STĚNA ANGLICKÉHO DVORKU | Půdorys 1.PP | POHLEDOVY BETON 0.08 m |  | STĚNA ANGLICKÉHO DVORKU | A | 1364HWa0798491577 | m3 | Celá stěna | Nový | Betonářské práce | POHLEDOVY BETON | no | 1364Stě0798491583 | m3 | I.AD1 | 0 | 0.08 | 2.25 | 2.25 | 0.18 | 1 | 0.18 | 0.08 | 2.25 | NEMSOK - Object Layer Attributes #1, Kód prvku: OV00.02.0001; Object Layer Attributes #1, Podlaží: 1.PP; Object Layer Attributes #1, Statická funkce: Ne
STĚNA ANGLICKÉHO DVORKU | Půdorys 1.PP | POHLEDOVY BETON 0.08 m |  | STĚNA ANGLICKÉHO DVORKU | A | 1364HWa0798491580 | m3 | Celá stěna | Nový | Betonářské práce | POHLEDOVY BETON | no | 1364Stě0798491588 | m3 | I.AD1 | 0 | 0.08 | 2.993 | 2.993 | 0.239 | 1.33 | 0.239 | 0.106 | 2.25 | NEMSOK - Object Layer Attributes #1, Kód prvku: OV00.02.0001; Object Layer Attributes #1, Podlaží: 1.PP; Object Layer Attributes #1, Statická funkce: Ne
STĚNA ANGLICKÉHO DVORKU | Půdorys 1.PP | POHLEDOVY BETON 0.08 m |  | STĚNA ANGLICKÉHO DVORKU | A | 1364HWa0798491584 | m3 | Celá stěna | Nový | Betonářské práce | POHLEDOVY BETON | no | 1364Stě0798491586 | m3 | I.AD1 | 0 | 0.08 | 2.43 | 2.43 | 0.194 | 1.08 | 0.194 | 0.086 | 2.25 | NEMSOK - Object Layer Attributes #1, Kód prvku: OV00.02.0001; Object Layer Attributes #1, Podlaží: 1.PP; Object Layer Attributes #1, Statická funkce: Ne
STĚNA ANGLICKÉHO DVORKU | Půdorys 1.PP | POHLEDOVY BETON 0.08 m |  | STĚNA ANGLICKÉHO DVORKU | A | 1364HWa0798494988 | m3 | Celá stěna | Nový | Betonářské práce | POHLEDOVY BETON | no | 1364Stě0798495175 | m3 | I.AD6 | 0 | 0.08 | 1.944 | 1.944 | 0.156 | 1.08 | 0.156 | 0.086 | 1.8 | NEMSOK - Object Layer Attributes #1, Kód prvku: OV00.02.0001; Object Layer Attributes #1, Podlaží: 1.PP; Object Layer Attributes #1, Statická funkce: Ne
STĚNA ANGLICKÉHO DVORKU | Půdorys 1.PP | POHLEDOVY BETON 0.08 m |  | STĚNA ANGLICKÉHO DVORKU | A | 1364HWa0798494990 | m3 | Celá stěna | Nový | Betonářské práce | POHLEDOVY BETON | no | 1364Stě0798495700 | m3 | I.AD6 | 0 | 0.08 | 1.08 | 1.08 | 0.086 | 0.6 | 0.086 | 0.048 | 1.8 | NEMSOK - Object Layer Attributes #1, Kód prvku: OV00.02.0001; Object Layer Attributes #1, Podlaží: 1.PP; Object Layer Attributes #1, Statická funkce: Ne
ZELEZOBETONOVÁ KCE | Půdorys 1.PP | ZELEZOBETONOVÁ KCE 0.25 m |  | ZELEZOBETONOVÁ KCE |  | 1364HWa0798495104 | m3 | Celá stěna | Nový | Betonářské práce | ZELEZOBETONOVÁ KCE | yes | 1364Stě0798495689 | m3 | Stěna |  | 0.25 | 37.824 | 31.095 | 9.456 | 11.82 | 7.774 | 2.955 | 3.2 | NEMSOK - Object Layer Attributes #1, Kód prvku: SN02.02.0003; Object Layer Attributes #1, Funkce: Ne; Object Layer Attributes #1, U-hodnota: 3.05; Object Layer Attributes #1, Podlaží: 1.PP; Object Layer Attributes #1, Požární odolnost: A; Object Layer Attributes #1, Třída pevnosti ocele: B500B; Object Layer Attributes #1, Stupeň vyztužení: 150; Object Layer Attributes #1, Třída pevnosti betonu: C25/30-XC1; Object Layer Attributes #1, Krytí výztuže: 25mm; Object Layer Attributes #1, Statická funkce: Ano
ZELEZOBETONOVÁ KCE | Půdorys 1.PP | ZELEZOBETONOVÁ KCE 0.2 m |  | ZELEZOBETONOVÁ KCE |  | 1364HWa0798495106 | m3 | Celá stěna | Nový | Betonářské práce | ZELEZOBETONOVÁ KCE | yes | 1364Stě0798495653 | m3 | Stěna |  | 0.2 | 16.48 | 16.44 | 3.296 | 5.15 | 3.288 | 1.03 | 3.2 | NEMSOK - Object Layer Attributes #1, Kód prvku: SN02.02.0002; Object Layer Attributes #1, Funkce: Ne; Object Layer Attributes #1, U-hodnota: 3.37; Object Layer Attributes #1, Podlaží: 1.PP; Object Layer Attributes #1, Požární odolnost: A; Object Layer Attributes #1, Třída pevnosti ocele: B500B; Object Layer Attributes #1, Stupeň vyztužení: 150; Object Layer Attributes #1, Třída pevnosti betonu: C25/30-XC1; Object Layer Attributes #1, Krytí výztuže: 25mm; Object Layer Attributes #1, Statická funkce: Ano
ZELEZOBETONOVÁ KCE | Půdorys 1.PP | ZELEZOBETONOVÁ KCE 0.3 m |  | ZELEZOBETONOVÁ KCE |  | 1364HWa0798495109 | m3 | Celá stěna | Nový | Betonářské práce | ZELEZOBETONOVÁ KCE | yes | 1364Stě0798495769 | m3 | Stěna |  | 0.3 | 8.16 | 8.16 | 2.448 | 2.55 | 2.448 | 0.765 | 3.2 | NEMSOK - Object Layer Attributes #1, Kód prvku: SN02.02.0005; Object Layer Attributes #1, Funkce: Ne; Object Layer Attributes #1, U-hodnota: 2.78; Object Layer Attributes #1, Podlaží: 1.PP; Object Layer Attributes #1, Požární odolnost: A; Object Layer Attributes #1, Třída pevnosti ocele: B500B; Object Layer Attributes #1, Stupeň vyztužení: 150; Object Layer Attributes #1, Třída pevnosti betonu: C25/30-XC1; Object Layer Attributes #1, Krytí výztuže: 25mm; Object Layer Attributes #1, Statická funkce: Ano
ZELEZOBETONOVÁ KCE | Půdorys 1.PP | ZELEZOBETONOVÁ KCE 0.2 m |  | ZELEZOBETONOVÁ KCE |  | 1364HWa0798495132 | m3 | Celá stěna | Nový | Betonářské práce | ZELEZOBETONOVÁ KCE | yes | 1364Stě0798495185 | m3 | Stěna |  | 0.2 | 0.816 | 0.816 | 0.163 | 0.255 | 0.163 | 0.051 | 3.2 | NEMSOK - Object Layer Attributes #1, Kód prvku: SN02.02.0001; Object Layer Attributes #1, Funkce: Ne; Object Layer Attributes #1, U-hodnota: 3.37; Object Layer Attributes #1, Podlaží: 1.PP; Object Layer Attributes #1, Požární odolnost: A; Object Layer Attributes #1, Třída pevnosti ocele: B500B; Object Layer Attributes #1, Stupeň vyztužení: 150; Object Layer Attributes #1, Třída pevnosti betonu: C25/30-XC1; Object Layer Attributes #1, Krytí výztuže: 25mm; Object Layer Attributes #1, Statická funkce: Ano
STĚNA ANGLICKÉHO DVORKU | Půdorys 1.PP | POHLEDOVY BETON 0.08 m |  | STĚNA ANGLICKÉHO DVORKU | A | 1364HWa0798495156 | m3 | Celá stěna | Nový | Betonářské práce | POHLEDOVY BETON | no | 1364Stě0798495698 | m3 | I.AD6 | 0 | 0.08 | 1.224 | 1.224 | 0.098 | 0.68 | 0.098 | 0.054 | 1.8 | NEMSOK - Object Layer Attributes #1, Kód prvku: OV00.02.0001; Object Layer Attributes #1, Podlaží: 1.PP; Object Layer Attributes #1, Statická funkce: Ne
ZELEZOBETONOVÁ KCE | Půdorys 1.PP | ZELEZOBETONOVÁ KCE 0.3 m, PERIMETR 0.22 m |  | ZELEZOBETONOVÁ KCE |  | 1364HWa0798495162 | m3 | Celá stěna | Nový | Betonářské práce | ZELEZOBETONOVÁ KCE | yes | 1364Stě0798495902 | m3 | Stěna |  | 0.52 | 38.998 | 33.298 | 18.804 | 11.06 | 15.78 | 5.718 | 3.4 | NEMSOK - Object Layer Attributes #2, 2D interakce: yes; Object Layer Attributes #2, Status: Nový; Object Layer Attributes #2, Práce: Zateplovací systémy; Object Layer Attributes #2, Materiál: PERIMETR; Object Layer Attributes #2, Allright_Stavebni_dil_ID: 1364Stě0798495897; Object Layer Attributes #2, Jednotka: m3; Object Layer Attributes #2, Název_objektu: Stěna; Object Layer Attributes #2, Staticky nosná konstrukce: no; Object Layer Attributes #1, Kód prvku: SN02.02.0006; Object Layer Attributes #1, Funkce: Ne; Object Layer Attributes #1, U-hodnota: 2.78; Object Layer Attributes #1, Podlaží: 1.PP; Object Layer Attributes #1, Požární odolnost: A; Object Layer Attributes #1, Třída pevnosti ocele: B500B; Object Layer Attributes #1, Stupeň vyztužení: 150; Object Layer Attributes #1, Třída pevnosti betonu: C25/30-XC1; Object Layer Attributes #1, Krytí výztuže: 25mm; Object Layer Attributes #1, Statická funkce: Ano; Object Layer Attributes #2, Kód prvku: TI02.02.0003; Object Layer Attributes #2, U-hodnota: 2.78; Object Layer Attributes #2, Požární odolnost: E; Object Layer Attributes #2, Součinitel prostupu tepla: 0.034; Object Layer Attributes #2, Součinitel difúzního odporu: 40 - 100; Object Layer Attributes #2, Způsob spojení vrstev: Lepený
ZELEZOBETONOVÁ KCE | Půdorys 1.PP | ZELEZOBETONOVÁ KCE 0.3 m |  | ZELEZOBETONOVÁ KCE |  | 1364HWa0798495245 | m3 | Celá stěna | Nový | Betonářské práce | ZELEZOBETONOVÁ KCE | yes | 1364Stě0798495759 | m3 | Stěna |  | 0.3 | 26.88 | 26.88 | 8.064 | 8.4 | 8.064 | 2.52 | 3.2 | NEMSOK - Object Layer Attributes #1, Kód prvku: SN02.02.0004; Object Layer Attributes #1, Funkce: Ne; Object Layer Attributes #1, U-hodnota: 2.78; Object Layer Attributes #1, Podlaží: 1.PP; Object Layer Attributes #1, Požární odolnost: A; Object Layer Attributes #1, Třída pevnosti ocele: B500B; Object Layer Attributes #1, Stupeň vyztužení: 150; Object Layer Attributes #1, Třída pevnosti betonu: C25/30-XC1; Object Layer Attributes #1, Krytí výztuže: 25mm; Object Layer Attributes #1, Statická funkce: Ano
STĚNA ANGLICKÉHO DVORKU | Půdorys 1.PP | POHLEDOVY BETON 0.08 m |  | STĚNA ANGLICKÉHO DVORKU | A | 1364HWa0798495782 | m3 | Celá stěna | Nový | Betonářské práce | POHLEDOVY BETON | no | 1364Stě0798495829 | m3 | I.AD4 | 0 | 0.08 | 2.646 | 2.646 | 0.212 | 1.08 | 0.212 | 0.086 | 2.45 | NEMSOK - Object Layer Attributes #1, Kód prvku: OV00.02.0001; Object Layer Attributes #1, Podlaží: 1.PP; Object Layer Attributes #1, Statická funkce: Ne
STĚNA ANGLICKÉHO DVORKU | Půdorys 1.PP | POHLEDOVY BETON 0.08 m |  | STĚNA ANGLICKÉHO DVORKU | A | 1364HWa0798495842 | m3 | Celá stěna | Nový | Betonářské práce | POHLEDOVY BETON | no | 1364Stě0798495885 | m3 | I.AD5 | 0 | 0.08 | 2.8 | 2.8 | 0.224 | 1 | 0.224 | 0.08 | 2.8 | NEMSOK - Object Layer Attributes #1, Kód prvku: OV00.02.0001; Object Layer Attributes #1, Podlaží: 1.PP; Object Layer Attributes #1, Statická funkce: Ne
STĚNA ANGLICKÉHO DVORKU | Půdorys 1.PP | POHLEDOVY BETON 0.08 m |  | STĚNA ANGLICKÉHO DVORKU | A | 1364HWa0798495844 | m3 | Celá stěna | Nový | Betonářské práce | POHLEDOVY BETON | no | 1364Stě0798495891 | m3 | I.AD5 | 0 | 0.08 | 5.964 | 5.964 | 0.477 | 2.13 | 0.477 | 0.17 | 2.8 | NEMSOK - Object Layer Attributes #1, Kód prvku: OV00.02.0001; Object Layer Attributes #1, Podlaží: 1.PP; Object Layer Attributes #1, Statická funkce: Ne
STĚNA ANGLICKÉHO DVORKU | Půdorys 1.PP | POHLEDOVY BETON 0.08 m |  | STĚNA ANGLICKÉHO DVORKU | A | 1364HWa0798495846 | m3 | Celá stěna | Nový | Betonářské práce | POHLEDOVY BETON | no | 1364Stě0798495887 | m3 | I.AD5 | 0 | 0.08 | 3.024 | 3.024 | 0.242 | 1.08 | 0.242 | 0.086 | 2.8 | NEMSOK - Object Layer Attributes #1, Kód prvku: OV00.02.0001; Object Layer Attributes #1, Podlaží: 1.PP; Object Layer Attributes #1, Statická funkce: Ne
YTONG 100 | Půdorys 1.PP | YTONG 100 0.1 m |  | YTONG 100 |  | 1364HWa0798495915 | m3 | Celá stěna | Nový | Zednické práce | YTONG 100 | no | 1364Stě0798495922 | m3 | Stěna |  | 0.1 | 1.8 | 1.8 | 0.18 | 1.2 | 0.18 | 0.12 | 1.5 | NEMSOK - Object Layer Attributes #1, Kód prvku: SN06.02.1008; Object Layer Attributes #1, Funkce: Ne; Object Layer Attributes #1, U-hodnota: 1.111; Object Layer Attributes #1, Podlaží: 1.PP; Object Layer Attributes #1, Neprůzvučnost: 35 dB; Object Layer Attributes #1, Požární odolnost: EI 120; Object Layer Attributes #1, Pevnost zdiva: 1,92 N/mm2; Object Layer Attributes #1, Funkce (venkovní): Ne; Object Layer Attributes #1, Statická funkce: Ne
ZELEZOBETONOVÁ KCE | Půdorys 1.PP | ZELEZOBETONOVÁ KCE 0.225 m |  | ZELEZOBETONOVÁ KCE | A | 1364HWa0798495917 | m3 | Celá stěna | Nový | Betonářské práce | ZELEZOBETONOVÁ KCE | no | 1364Stě0798495920 | m3 | Stěna | 0 | 0.225 | 1.8 | 1.8 | 0.405 | 1.2 | 0.405 | 0.27 | 1.5 | NEMSOK - Object Layer Attributes #1, Kód prvku: SN02.02.0016; Object Layer Attributes #1, Funkce: Ne; Object Layer Attributes #1, U-hodnota: 3.23; Object Layer Attributes #1, Podlaží: 1.PP; Object Layer Attributes #1, Požární odolnost: A; Object Layer Attributes #1, Třída pevnosti ocele: B500B; Object Layer Attributes #1, Stupeň vyztužení: 150; Object Layer Attributes #1, Třída pevnosti betonu: C25/30-XC1; Object Layer Attributes #1, Krytí výztuže: 25mm; Object Layer Attributes #1, Statická funkce: Ne
YTONG 100 | Půdorys 1.PP | YTONG 100 0.1 m |  | YTONG 100 |  | 1364HWa0798495923 | m3 | Celá stěna | Nový | Zednické práce | YTONG 100 | no | 1364Stě0798495930 | m3 | Stěna |  | 0.1 | 1.8 | 1.8 | 0.18 | 1.2 | 0.18 | 0.12 | 1.5 | NEMSOK - Object Layer Attributes #1, Kód prvku: SN06.02.1009; Object Layer Attributes #1, Funkce: Ne; Object Layer Attributes #1, U-hodnota: 1.111; Object Layer Attributes #1, Podlaží: 1.PP; Object Layer Attributes #1, Neprůzvučnost: 35 dB; Object Layer Attributes #1, Požární odolnost: EI 120; Object Layer Attributes #1, Pevnost zdiva: 1,92 N/mm2; Object Layer Attributes #1, Funkce (venkovní): Ne; Object Layer Attributes #1, Statická funkce: Ne
ZELEZOBETONOVÁ KCE | Půdorys 1.PP | ZELEZOBETONOVÁ KCE 0.225 m |  | ZELEZOBETONOVÁ KCE | A | 1364HWa0798495925 | m3 | Celá stěna | Nový | Betonářské práce | ZELEZOBETONOVÁ KCE | no | 1364Stě0798495928 | m3 | Stěna | 0 | 0.225 | 1.8 | 1.8 | 0.405 | 1.2 | 0.405 | 0.27 | 1.5 | NEMSOK - Object Layer Attributes #1, Kód prvku: SN02.02.0017; Object Layer Attributes #1, Funkce: Ne; Object Layer Attributes #1, U-hodnota: 3.23; Object Layer Attributes #1, Podlaží: 1.PP; Object Layer Attributes #1, Požární odolnost: A; Object Layer Attributes #1, Třída pevnosti ocele: B500B; Object Layer Attributes #1, Stupeň vyztužení: 150; Object Layer Attributes #1, Třída pevnosti betonu: C25/30-XC1; Object Layer Attributes #1, Krytí výztuže: 25mm; Object Layer Attributes #1, Statická funkce: Ne
ZELEZOBETONOVÁ KCE | Půdorys 1.PP | ZELEZOBETONOVÁ KCE 0.3 m |  | ZELEZOBETONOVÁ KCE |  | 1364HWa0798496812 | m3 | Celá stěna | Nový | Betonářské práce | ZELEZOBETONOVÁ KCE | yes | 1364Stě0798496813 | m3 | Stěna |  | 0.3 | 11.904 | 11.904 | 3.571 | 3.72 | 3.571 | 1.116 | 3.2 | NEMSOK - Object Layer Attributes #1, Kód prvku: SN02.02.0007; Object Layer Attributes #1, Funkce: Ne; Object Layer Attributes #1, U-hodnota: 2.78; Object Layer Attributes #1, Podlaží: 1.PP; Object Layer Attributes #1, Požární odolnost: A; Object Layer Attributes #1, Třída pevnosti ocele: B500B; Object Layer Attributes #1, Stupeň vyztužení: 150; Object Layer Attributes #1, Třída pevnosti betonu: C25/30-XC1; Object Layer Attributes #1, Krytí výztuže: 25mm; Object Layer Attributes #1, Statická funkce: Ano
ZELEZOBETONOVÁ KCE | Půdorys 1.PP | ZELEZOBETONOVÁ KCE 0.3 m |  | ZELEZOBETONOVÁ KCE |  | 1364HWa0798498326 | m3 | Celá stěna | Nový | Betonářské práce | ZELEZOBETONOVÁ KCE | yes | 1364Stě0798498327 | m3 | Stěna |  | 0.3 | 11.744 | 11.695 | 3.523 | 3.67 | 3.509 | 1.101 | 3.2 | NEMSOK - Object Layer Attributes #1, Kód prvku: SN02.02.0008; Object Layer Attributes #1, Funkce: Ne; Object Layer Attributes #1, U-hodnota: 2.78; Object Layer Attributes #1, Podlaží: 1.PP; Object Layer Attributes #1, Požární odolnost: A; Object Layer Attributes #1, Třída pevnosti ocele: B500B; Object Layer Attributes #1, Stupeň vyztužení: 150; Object Layer Attributes #1, Třída pevnosti betonu: C25/30-XC1; Object Layer Attributes #1, Krytí výztuže: 25mm; Object Layer Attributes #1, Statická funkce: Ano
ZELEZOBETONOVÁ KCE | Půdorys 1.PP | ZELEZOBETONOVÁ KCE 0.3 m |  | ZELEZOBETONOVÁ KCE |  | 1364HWa0798498422 | m3 | Celá stěna | Nový | Betonářské práce | ZELEZOBETONOVÁ KCE | yes | 1364Stě0798498424 | m3 | Stěna |  | 0.3 | 15.692 | 15.692 | 4.708 | 4.904 | 4.708 | 1.471 | 3.2 | NEMSOK - Object Layer Attributes #1, Kód prvku: SN02.02.0009; Object Layer Attributes #1, Funkce: Ne; Object Layer Attributes #1, U-hodnota: 2.78; Object Layer Attributes #1, Podlaží: 1.PP; Object Layer Attributes #1, Požární odolnost: A; Object Layer Attributes #1, Funkce (venkovní): Ne; Object Layer Attributes #1, Třída pevnosti ocele: B500B; Object Layer Attributes #1, Stupeň vyztužení: 150; Object Layer Attributes #1, Třída pevnosti betonu: C25/30-XC1; Object Layer Attributes #1, Krytí výztuže: 25mm; Object Layer Attributes #1, Statická funkce: Ano
ZELEZOBETONOVÁ KCE | Půdorys 1.PP | ZELEZOBETONOVÁ KCE 0.2 m |  | ZELEZOBETONOVÁ KCE |  | 1364HWa0798498654 | m3 | Celá stěna | Nový | Betonářské práce | ZELEZOBETONOVÁ KCE | yes | 1364Stě0798498656 | m3 | Stěna |  | 0.2 | 0.816 | 0.816 | 0.163 | 0.255 | 0.163 | 0.051 | 3.2 | NEMSOK - Object Layer Attributes #1, Kód prvku: SN02.02.0010; Object Layer Attributes #1, Funkce: Ne; Object Layer Attributes #1, U-hodnota: 3.37; Object Layer Attributes #1, Podlaží: 1.PP; Object Layer Attributes #1, Požární odolnost: A; Object Layer Attributes #1, Třída pevnosti ocele: B500B; Object Layer Attributes #1, Stupeň vyztužení: 150; Object Layer Attributes #1, Třída pevnosti betonu: C25/30-XC1; Object Layer Attributes #1, Krytí výztuže: 25mm; Object Layer Attributes #1, Statická funkce: Ano
ZELEZOBETONOVÁ KCE | Půdorys 1.PP | ZELEZOBETONOVÁ KCE 0.2 m |  | ZELEZOBETONOVÁ KCE |  | 1364HWa0798498661 | m3 | Celá stěna | Nový | Betonářské práce | ZELEZOBETONOVÁ KCE | yes | 1364Stě0798498663 | m3 | Stěna |  | 0.2 | 0.816 | 0.816 | 0.163 | 0.255 | 0.163 | 0.051 | 3.2 | NEMSOK - Object Layer Attributes #1, Kód prvku: SN02.02.0011; Object Layer Attributes #1, Funkce: Ne; Object Layer Attributes #1, U-hodnota: 3.37; Object Layer Attributes #1, Podlaží: 1.PP; Object Layer Attributes #1, Požární odolnost: A; Object Layer Attributes #1, Třída pevnosti ocele: B500B; Object Layer Attributes #1, Stupeň vyztužení: 150; Object Layer Attributes #1, Třída pevnosti betonu: C25/30-XC1; Object Layer Attributes #1, Krytí výztuže: 25mm; Object Layer Attributes #1, Statická funkce: Ano
ZELEZOBETONOVÁ KCE | Půdorys 1.PP | ZELEZOBETONOVÁ KCE 0.3 m |  | ZELEZOBETONOVÁ KCE |  | 1364HWa0798499181 | m3 | Celá stěna | Nový | Betonářské práce | ZELEZOBETONOVÁ KCE | yes | 1364Stě0798499182 | m3 | Stěna |  | 0.3 | 23.748 | 23.748 | 7.124 | 7.421 | 7.124 | 2.226 | 3.2 | NEMSOK - Object Layer Attributes #1, Kód prvku: SN02.02.0012; Object Layer Attributes #1, Funkce: Ne; Object Layer Attributes #1, U-hodnota: 2.78; Object Layer Attributes #1, Podlaží: 1.PP; Object Layer Attributes #1, Požární odolnost: A; Object Layer Attributes #1, Třída pevnosti ocele: B500B; Object Layer Attributes #1, Stupeň vyztužení: 150; Object Layer Attributes #1, Třída pevnosti betonu: C25/30-XC1; Object Layer Attributes #1, Krytí výztuže: 25mm; Object Layer Attributes #1, Statická funkce: Ano
STĚNA ANGLICKÉHO DVORKU | Půdorys 1.PP | POHLEDOVY BETON 0.08 m |  | STĚNA ANGLICKÉHO DVORKU | A | 1364HWa0798499909 | m3 | Celá stěna | Nový | Betonářské práce | POHLEDOVY BETON | no | 1364Stě0798499922 | m3 | I.AD3 | 0 | 0.08 | 0.952 | 0.952 | 0.076 | 0.68 | 0.076 | 0.054 | 1.4 | NEMSOK - Object Layer Attributes #1, Kód prvku: OV00.02.0001; Object Layer Attributes #1, Podlaží: 1.PP; Object Layer Attributes #1, Statická funkce: Ne
SDK SVISLA CAST PODHLEDU | Půdorys 1.PP | SDK SVISLA CAST PODHLEDU 0.04 m |  | SDK SVISLA CAST PODHLEDU |  | 1364HWa0798513096 | m3 | Celá stěna | Nový | Suché stavební práce | SDK SVISLA CAST PODHLEDU | no | 1364Stě0798513097 | m3 | Stěna |  | 0.04 | 0.96 | 0.96 | 0.038 | 2.4 | 0.038 | 0.096 | 0.4 | NEMSOK - Object Layer Attributes #1, Kód prvku: PH01.02.0001; Object Layer Attributes #1, Požární odolnost: bez požadavku; Object Layer Attributes #1, Statická funkce: Ne; Object Layer Attributes #1, Výška svěšení: 0.65 m; Object Layer Attributes #1, Únosnost bodová: 0.5 kg
YTONG 125 | Půdorys 1.PP | YTONG 125 0.125 m |  | YTONG 125 |  | 1364HWa0798521552 | m3 | Celá stěna | Nový | Zednické práce | YTONG 125 | no | 1364Stě0798521553 | m3 | Stěna |  | 0.125 | 2.475 | 0.355 | 0.309 | 1.1 | 0.044 | 0.138 | 2.25 | NEMSOK - Object Layer Attributes #1, Kód prvku: SN06.02.1010; Object Layer Attributes #1, Funkce: Ne; Object Layer Attributes #1, U-hodnota: 0.926; Object Layer Attributes #1, Podlaží: 1.PP; Object Layer Attributes #1, Neprůzvučnost: 37 dB; Object Layer Attributes #1, Požární odolnost: EI 180; Object Layer Attributes #1, Pevnost zdiva: 1,92 N/mm2; Object Layer Attributes #1, Funkce (venkovní): Ne; Object Layer Attributes #1, Statická funkce: Ne
YTONG 125 | Půdorys 1.PP | YTONG 125 0.125 m |  | YTONG 125 |  | 1364HWa0798521666 | m3 | Celá stěna | Nový | Zednické práce | YTONG 125 | no | 1364Stě0798521667 | m3 | Stěna |  | 0.125 | 2.025 | 0.329 | 0.253 | 0.9 | 0.041 | 0.112 | 2.25 | NEMSOK - Object Layer Attributes #1, Kód prvku: SN06.02.1011; Object Layer Attributes #1, Funkce: Ne; Object Layer Attributes #1, U-hodnota: 0.926; Object Layer Attributes #1, Podlaží: 1.PP; Object Layer Attributes #1, Neprůzvučnost: 37 dB; Object Layer Attributes #1, Požární odolnost: EI 180; Object Layer Attributes #1, Pevnost zdiva: 1,92 N/mm2; Object Layer Attributes #1, Funkce (venkovní): Ne; Object Layer Attributes #1, Statická funkce: Ne
YTONG 125 | Půdorys 1.PP | YTONG 125 0.125 m |  | YTONG 125 |  | 1364HWa0798521729 | m3 | Celá stěna | Nový | Zednické práce | YTONG 125 | no | 1364Stě0798521730 | m3 | Stěna |  | 0.125 | 2.475 | 0.355 | 0.309 | 1.1 | 0.044 | 0.138 | 2.25 | NEMSOK - Object Layer Attributes #1, Kód prvku: SN06.02.1012; Object Layer Attributes #1, Funkce: Ne; Object Layer Attributes #1, U-hodnota: 0.926; Object Layer Attributes #1, Podlaží: 1.PP; Object Layer Attributes #1, Neprůzvučnost: 37 dB; Object Layer Attributes #1, Požární odolnost: EI 180; Object Layer Attributes #1, Pevnost zdiva: 1,92 N/mm2; Object Layer Attributes #1, Funkce (venkovní): Ne; Object Layer Attributes #1, Statická funkce: Ne
YTONG 125 | Půdorys 1.PP | YTONG 125 0.125 m |  | YTONG 125 |  | 1364HWa0798521799 | m3 | Celá stěna | Nový | Zednické práce | YTONG 125 | no | 1364Stě0798521800 | m3 | Stěna |  | 0.125 | 2.7 | 0.58 | 0.337 | 1.2 | 0.072 | 0.15 | 2.25 | NEMSOK - Object Layer Attributes #1, Kód prvku: SN06.02.1013; Object Layer Attributes #1, Funkce: Ne; Object Layer Attributes #1, U-hodnota: 0.926; Object Layer Attributes #1, Podlaží: 1.PP; Object Layer Attributes #1, Neprůzvučnost: 37 dB; Object Layer Attributes #1, Požární odolnost: EI 180; Object Layer Attributes #1, Pevnost zdiva: 1,92 N/mm2; Object Layer Attributes #1, Funkce (venkovní): Ne; Object Layer Attributes #1, Statická funkce: Ne
YTONG 250 | Půdorys 1.PP | YTONG 250 0.25 m |  | YTONG 250 | REI 180 | 1364HWa0798522124 | m3 | Celá stěna | Nový | Zednické práce | YTONG 250 | no | 1364Stě0798522128 | m3 | Stěna | 0.637 | 0.25 | 2.025 | 2.025 | 0.506 | 0.9 | 0.506 | 0.225 | 2.25 | Pset_WallCommon - AcousticRating: 47 dB; NEMSOK - Object Layer Attributes #1, Kód prvku: SN06.02.0004; Object Layer Attributes #1, Funkce: Ne; Object Layer Attributes #1, U-hodnota: 0.429; Object Layer Attributes #1, Podlaží: 1.PP; Object Layer Attributes #1, Neprůzvučnost: 43 dB; Object Layer Attributes #1, Požární odolnost: REI 180; Object Layer Attributes #1, Pevnost zdiva: 2,32 N/mm2; Object Layer Attributes #1, Funkce (venkovní): Ne; Object Layer Attributes #1, Statická funkce: Ne
STĚNA ANGLICKÉHO DVORKU | Půdorys 1.PP | POHLEDOVY BETON 0.08 m |  | STĚNA ANGLICKÉHO DVORKU | A | 1364HWa0798523109 | m3 | Celá stěna | Nový | Betonářské práce | POHLEDOVY BETON | no | 1364Stě0798523110 | m3 | I.AD3 | 0 | 0.08 | 1.512 | 1.512 | 0.121 | 1.08 | 0.121 | 0.086 | 1.4 | NEMSOK - Object Layer Attributes #1, Kód prvku: OV00.02.0001; Object Layer Attributes #1, Podlaží: 1.PP; Object Layer Attributes #1, Statická funkce: Ne
STĚNA ANGLICKÉHO DVORKU | Půdorys 1.PP | POHLEDOVY BETON 0.08 m |  | STĚNA ANGLICKÉHO DVORKU | A | 1364HWa0798523120 | m3 | Celá stěna | Nový | Betonářské práce | POHLEDOVY BETON | no | 1364Stě0798523121 | m3 | I.AD3 | 0 | 0.08 | 0.84 | 0.84 | 0.067 | 0.6 | 0.067 | 0.048 | 1.4 | NEMSOK - Object Layer Attributes #1, Kód prvku: OV00.02.0001; Object Layer Attributes #1, Podlaží: 1.PP; Object Layer Attributes #1, Statická funkce: Ne
STĚNA ANGLICKÉHO DVORKU | Půdorys 1.PP | POHLEDOVY BETON 0.08 m |  | STĚNA ANGLICKÉHO DVORKU | A | 1364HWa0798523184 | m3 | Celá stěna | Nový | Betonářské práce | POHLEDOVY BETON | no | 1364Stě0798523185 | m3 | I.AD4 | 0 | 0.08 | 5.219 | 5.219 | 0.417 | 2.13 | 0.417 | 0.17 | 2.45 | NEMSOK - Object Layer Attributes #1, Kód prvku: OV00.02.0001; Object Layer Attributes #1, Podlaží: 1.PP; Object Layer Attributes #1, Statická funkce: Ne
STĚNA ANGLICKÉHO DVORKU | Půdorys 1.PP | POHLEDOVY BETON 0.08 m |  | STĚNA ANGLICKÉHO DVORKU | A | 1364HWa0798523195 | m3 | Celá stěna | Nový | Betonářské práce | POHLEDOVY BETON | no | 1364Stě0798523196 | m3 | I.AD4 | 0 | 0.08 | 2.45 | 2.45 | 0.196 | 1 | 0.196 | 0.08 | 2.45 | NEMSOK - Object Layer Attributes #1, Kód prvku: OV00.02.0001; Object Layer Attributes #1, Podlaží: 1.PP; Object Layer Attributes #1, Statická funkce: Ne
YTONG 125 | Půdorys 1.PP | YTONG 125 0.125 m |  | YTONG 125 |  | 1364HWa0798528547 | m3 | Celá stěna | Nový | Zednické práce | YTONG 125 | no | 1364Stě0798528549 | m3 | Stěna |  | 0.125 | 2.7 | 0.792 | 0.338 | 1.2 | 0.099 | 0.15 | 2.25 | NEMSOK - Object Layer Attributes #1, Kód prvku: SN06.02.1014; Object Layer Attributes #1, Funkce: Ne; Object Layer Attributes #1, U-hodnota: 0.926; Object Layer Attributes #1, Podlaží: 1.PP; Object Layer Attributes #1, Neprůzvučnost: 37 dB; Object Layer Attributes #1, Požární odolnost: EI 180; Object Layer Attributes #1, Pevnost zdiva: 1,92 N/mm2; Object Layer Attributes #1, Funkce (venkovní): Ne; Object Layer Attributes #1, Statická funkce: Ne
YTONG 125 | Půdorys 1.PP | YTONG 125 0.125 m |  | YTONG 125 |  | 1364HWa0798529199 | m3 | Celá stěna | Nový | Zednické práce | YTONG 125 | no | 1364Stě0798529200 | m3 | Stěna |  | 0.125 | 3.15 | 0.606 | 0.394 | 1.4 | 0.076 | 0.175 | 2.25 | NEMSOK - Object Layer Attributes #1, Kód prvku: SN06.02.1015; Object Layer Attributes #1, Funkce: Ne; Object Layer Attributes #1, U-hodnota: 0.926; Object Layer Attributes #1, Podlaží: 1.PP; Object Layer Attributes #1, Neprůzvučnost: 37 dB; Object Layer Attributes #1, Požární odolnost: EI 180; Object Layer Attributes #1, Pevnost zdiva: 1,92 N/mm2; Object Layer Attributes #1, Funkce (venkovní): Ne; Object Layer Attributes #1, Statická funkce: Ne
SDK SVISLA CAST PODHLEDU | Půdorys 1.PP | SDK SVISLA CAST PODHLEDU 0.04 m |  | SDK SVISLA CAST PODHLEDU |  | 1364HWa0798529800 | m3 | Celá stěna | Nový | Suché stavební práce | SDK SVISLA CAST PODHLEDU | no | 1364Stě0798529801 | m3 | Stěna |  | 0.04 | 1.28 | 1.28 | 0.051 | 4.265 | 0.051 | 0.171 | 0.3 | NEMSOK - Object Layer Attributes #1, Kód prvku: PH01.02.0002; Object Layer Attributes #1, Požární odolnost: bez požadavku; Object Layer Attributes #1, Statická funkce: Ne; Object Layer Attributes #1, Výška svěšení: 0.65 m; Object Layer Attributes #1, Únosnost bodová: 0.5 kg
SDK SVISLA CAST PODHLEDU | Půdorys 1.PP | SDK SVISLA CAST PODHLEDU 0.04 m |  | SDK SVISLA CAST PODHLEDU |  | 1364HWa0798529821 | m3 | Celá stěna | Nový | Suché stavební práce | SDK SVISLA CAST PODHLEDU | no | 1364Stě0798529822 | m3 | Stěna |  | 0.04 | 1.279 | 1.28 | 0.051 | 4.265 | 0.051 | 0.171 | 0.3 | NEMSOK - Object Layer Attributes #1, Kód prvku: PH01.02.0003; Object Layer Attributes #1, Požární odolnost: bez požadavku; Object Layer Attributes #1, Statická funkce: Ne; Object Layer Attributes #1, Výška svěšení: 0.65 m; Object Layer Attributes #1, Únosnost bodová: 0.5 kg
SDK SVISLA CAST PODHLEDU | Půdorys 1.PP | SDK SVISLA CAST PODHLEDU 0.04 m |  | SDK SVISLA CAST PODHLEDU |  | 1364HWa0798529851 | m3 | Celá stěna | Nový | Suché stavební práce | SDK SVISLA CAST PODHLEDU | no | 1364Stě0798529853 | m3 | Stěna |  | 0.04 | 0.54 | 0.54 | 0.022 | 1.8 | 0.022 | 0.072 | 0.3 | NEMSOK - Object Layer Attributes #1, Kód prvku: PH01.02.0004; Object Layer Attributes #1, Požární odolnost: bez požadavku; Object Layer Attributes #1, Statická funkce: Ne; Object Layer Attributes #1, Výška svěšení: 0.65 m; Object Layer Attributes #1, Únosnost bodová: 0.5 kg
SDK SVISLA CAST PODHLEDU | Půdorys 1.PP | SDK SVISLA CAST PODHLEDU 0.04 m |  | SDK SVISLA CAST PODHLEDU |  | 1364HWa0798529880 | m3 | Celá stěna | Nový | Suché stavební práce | SDK SVISLA CAST PODHLEDU | no | 1364Stě0798529881 | m3 | Stěna |  | 0.04 | 0.99 | 0.99 | 0.04 | 4.95 | 0.04 | 0.198 | 0.2 | NEMSOK - Object Layer Attributes #1, Kód prvku: PH01.02.0005; Object Layer Attributes #1, Požární odolnost: bez požadavku; Object Layer Attributes #1, Statická funkce: Ne; Object Layer Attributes #1, Výška svěšení: 0.55 m; Object Layer Attributes #1, Únosnost bodová: 0.5 kg
YTONG 125 | Půdorys 1.PP | YTONG 125 0.125 m |  | YTONG 125 |  | 1364HWa0798561809 | m3 | Celá stěna | Nový | Zednické práce | YTONG 125 | no | 1364Stě0798561810 | m3 | Stěna |  | 0.125 | 2.12 | 2.12 | 0.265 | 1 | 0.265 | 0.125 | 2.12 | NEMSOK - Object Layer Attributes #1, Kód prvku: SN06.02.1016; Object Layer Attributes #1, Funkce: Ne; Object Layer Attributes #1, U-hodnota: 0.926; Object Layer Attributes #1, Podlaží: 1.PP; Object Layer Attributes #1, Neprůzvučnost: 37 dB; Object Layer Attributes #1, Požární odolnost: EI 180; Object Layer Attributes #1, Pevnost zdiva: 1,92 N/mm2; Object Layer Attributes #1, Funkce (venkovní): Ne; Object Layer Attributes #1, Statická funkce: Ne
YTONG 100 | Půdorys 1.PP | YTONG 100 0.1 m |  | YTONG 100 |  | 1364HWa0798561845 | m3 | Celá stěna | Nový | Zednické práce | YTONG 100 | no | 1364Stě0798561846 | m3 | Stěna |  | 0.1 | 5.265 | 3.09 | 0.527 | 2.7 | 0.309 | 0.27 | 1.95 | NEMSOK - Object Layer Attributes #1, Kód prvku: SN06.02.1017; Object Layer Attributes #1, Funkce: Ne; Object Layer Attributes #1, U-hodnota: 1.111; Object Layer Attributes #1, Podlaží: 1.PP; Object Layer Attributes #1, Neprůzvučnost: 35 dB; Object Layer Attributes #1, Požární odolnost: EI 120; Object Layer Attributes #1, Pevnost zdiva: 1,92 N/mm2; Object Layer Attributes #1, Funkce (venkovní): Ne; Object Layer Attributes #1, Statická funkce: Ne
YTONG 100 | Půdorys 1.PP | YTONG 100 0.1 m |  | YTONG 100 |  | 1364HWa0798561882 | m3 | Celá stěna | Nový | Zednické práce | YTONG 100 | no | 1364Stě0798561886 | m3 | Stěna |  | 0.1 | 5.265 | 3.09 | 0.527 | 2.7 | 0.309 | 0.27 | 1.95 | NEMSOK - Object Layer Attributes #1, Kód prvku: SN06.02.1018; Object Layer Attributes #1, Funkce: Ne; Object Layer Attributes #1, U-hodnota: 1.111; Object Layer Attributes #1, Podlaží: 1.PP; Object Layer Attributes #1, Neprůzvučnost: 35 dB; Object Layer Attributes #1, Požární odolnost: EI 120; Object Layer Attributes #1, Pevnost zdiva: 1,92 N/mm2; Object Layer Attributes #1, Funkce (venkovní): Ne; Object Layer Attributes #1, Statická funkce: Ne
YTONG 100 | Půdorys 1.PP | YTONG 100 0.1 m |  | YTONG 100 |  | 1364HWa0798561896 | m3 | Celá stěna | Nový | Zednické práce | YTONG 100 | no | 1364Stě0798561897 | m3 | Stěna |  | 0.1 | 5.021 | 2.846 | 0.502 | 2.575 | 0.285 | 0.257 | 1.95 | NEMSOK - Object Layer Attributes #1, Kód prvku: SN06.02.1019; Object Layer Attributes #1, Funkce: Ne; Object Layer Attributes #1, U-hodnota: 1.111; Object Layer Attributes #1, Podlaží: 1.PP; Object Layer Attributes #1, Neprůzvučnost: 35 dB; Object Layer Attributes #1, Požární odolnost: EI 120; Object Layer Attributes #1, Pevnost zdiva: 1,92 N/mm2; Object Layer Attributes #1, Funkce (venkovní): Ne; Object Layer Attributes #1, Statická funkce: Ne
YTONG 100 | Půdorys 1.PP | YTONG 100 0.1 m |  | YTONG 100 |  | 1364HWa0798561913 | m3 | Celá stěna | Nový | Zednické práce | YTONG 100 | no | 1364Stě0798561914 | m3 | Stěna |  | 0.1 | 3.15 | 1.575 | 0.315 | 1.4 | 0.157 | 0.14 | 2.25 | NEMSOK - Object Layer Attributes #1, Kód prvku: SN06.02.1020; Object Layer Attributes #1, Funkce: Ne; Object Layer Attributes #1, U-hodnota: 1.111; Object Layer Attributes #1, Podlaží: 1.PP; Object Layer Attributes #1, Neprůzvučnost: 35 dB; Object Layer Attributes #1, Požární odolnost: EI 120; Object Layer Attributes #1, Pevnost zdiva: 1,92 N/mm2; Object Layer Attributes #1, Funkce (venkovní): Ne; Object Layer Attributes #1, Statická funkce: Ne
YTONG 100 | Půdorys 1.PP | YTONG 100 0.1 m |  | YTONG 100 |  | 1364HWa0798561936 | m3 | Celá stěna | Nový | Zednické práce | YTONG 100 | no | 1364Stě0798561937 | m3 | Stěna |  | 0.1 | 3.15 | 1.575 | 0.315 | 1.4 | 0.157 | 0.14 | 2.25 | NEMSOK - Object Layer Attributes #1, Kód prvku: SN06.02.1021; Object Layer Attributes #1, Funkce: Ne; Object Layer Attributes #1, U-hodnota: 1.111; Object Layer Attributes #1, Podlaží: 1.PP; Object Layer Attributes #1, Neprůzvučnost: 35 dB; Object Layer Attributes #1, Požární odolnost: EI 120; Object Layer Attributes #1, Pevnost zdiva: 1,92 N/mm2; Object Layer Attributes #1, Funkce (venkovní): Ne; Object Layer Attributes #1, Statická funkce: Ne
SDK SVISLA CAST PODHLEDU | Půdorys 1.PP | SDK SVISLA CAST PODHLEDU 0.04 m |  | SDK SVISLA CAST PODHLEDU |  | 1364HWa0798562000 | m3 | Celá stěna | Nový | Suché stavební práce | SDK SVISLA CAST PODHLEDU | no | 1364Stě0798562001 | m3 | Stěna |  | 0.04 | 0.194 | 0.194 | 0.008 | 0.485 | 0.008 | 0.019 | 0.4 | NEMSOK - Object Layer Attributes #1, Kód prvku: PH01.02.0006; Object Layer Attributes #1, Požární odolnost: bez požadavku; Object Layer Attributes #1, Statická funkce: Ne; Object Layer Attributes #1, Výška svěšení: 0.65 m; Object Layer Attributes #1, Únosnost bodová: 0.5 kg
SDK SVISLA CAST PODHLEDU | Půdorys 1.PP | SDK SVISLA CAST PODHLEDU 0.04 m |  | SDK SVISLA CAST PODHLEDU |  | 1364HWa0798562011 | m3 | Celá stěna | Nový | Suché stavební práce | SDK SVISLA CAST PODHLEDU | no | 1364Stě0798562012 | m3 | Stěna |  | 0.04 | 0.194 | 0.194 | 0.008 | 0.485 | 0.008 | 0.019 | 0.4 | NEMSOK - Object Layer Attributes #1, Kód prvku: PH01.02.0007; Object Layer Attributes #1, Požární odolnost: bez požadavku; Object Layer Attributes #1, Statická funkce: Ne; Object Layer Attributes #1, Výška svěšení: 0.65 m; Object Layer Attributes #1, Únosnost bodová: 0.5 kg
SDK SVISLA CAST PODHLEDU | Půdorys 1.PP | SDK SVISLA CAST PODHLEDU 0.04 m |  | SDK SVISLA CAST PODHLEDU |  | 1364HWa0798562022 | m3 | Celá stěna | Nový | Suché stavební práce | SDK SVISLA CAST PODHLEDU | no | 1364Stě0798562023 | m3 | Stěna |  | 0.04 | 0.25 | 0.25 | 0.01 | 2.5 | 0.01 | 0.1 | 0.1 | NEMSOK - Object Layer Attributes #1, Kód prvku: PH01.02.0008; Object Layer Attributes #1, Požární odolnost: bez požadavku; Object Layer Attributes #1, Statická funkce: Ne; Object Layer Attributes #1, Výška svěšení: 0.35 m; Object Layer Attributes #1, Únosnost bodová: 0.5 kg
SDK SVISLA CAST PODHLEDU | Půdorys 1.PP | SDK SVISLA CAST PODHLEDU 0.04 m |  | SDK SVISLA CAST PODHLEDU |  | 1364HWa0798562030 | m3 | Celá stěna | Nový | Suché stavební práce | SDK SVISLA CAST PODHLEDU | no | 1364Stě0798562031 | m3 | Stěna |  | 0.04 | 0.18 | 0.18 | 0.007 | 1.8 | 0.007 | 0.072 | 0.1 | NEMSOK - Object Layer Attributes #1, Kód prvku: PH01.02.0009; Object Layer Attributes #1, Požární odolnost: bez požadavku; Object Layer Attributes #1, Statická funkce: Ne; Object Layer Attributes #1, Výška svěšení: 0.35 m; Object Layer Attributes #1, Únosnost bodová: 0.5 kg
SDK SVISLA CAST PODHLEDU | Půdorys 1.PP | SDK SVISLA CAST PODHLEDU 0.04 m |  | SDK SVISLA CAST PODHLEDU |  | 1364HWa0798562046 | m3 | Celá stěna | Nový | Suché stavební práce | SDK SVISLA CAST PODHLEDU | no | 1364Stě0798562047 | m3 | Stěna |  | 0.04 | 0.308 | 0.308 | 0.012 | 3.075 | 0.012 | 0.123 | 0.1 | NEMSOK - Object Layer Attributes #1, Kód prvku: PH01.02.0010; Object Layer Attributes #1, Požární odolnost: bez požadavku; Object Layer Attributes #1, Statická funkce: Ne; Object Layer Attributes #1, Výška svěšení: 0.35 m; Object Layer Attributes #1, Únosnost bodová: 0.5 kg
SDK SVISLA CAST PODHLEDU | Půdorys 1.PP | SDK SVISLA CAST PODHLEDU 0.04 m |  | SDK SVISLA CAST PODHLEDU |  | 1364HWa0798562061 | m3 | Celá stěna | Nový | Suché stavební práce | SDK SVISLA CAST PODHLEDU | no | 1364Stě0798562062 | m3 | Stěna |  | 0.04 | 0.328 | 0.328 | 0.013 | 3.275 | 0.013 | 0.131 | 0.1 | NEMSOK - Object Layer Attributes #1, Kód prvku: PH01.02.0011; Object Layer Attributes #1, Požární odolnost: bez požadavku; Object Layer Attributes #1, Statická funkce: Ne; Object Layer Attributes #1, Výška svěšení: 0.35 m; Object Layer Attributes #1, Únosnost bodová: 0.5 kg
SDK SVISLA CAST PODHLEDU | Půdorys 1.PP | SDK SVISLA CAST PODHLEDU 0.04 m |  | SDK SVISLA CAST PODHLEDU |  | 1364HWa0798562078 | m3 | Celá stěna | Nový | Suché stavební práce | SDK SVISLA CAST PODHLEDU | no | 1364Stě0798562079 | m3 | Stěna |  | 0.04 | 0.327 | 0.328 | 0.013 | 3.275 | 0.013 | 0.131 | 0.1 | NEMSOK - Object Layer Attributes #1, Kód prvku: PH01.02.0012; Object Layer Attributes #1, Požární odolnost: bez požadavku; Object Layer Attributes #1, Statická funkce: Ne; Object Layer Attributes #1, Výška svěšení: 0.35 m; Object Layer Attributes #1, Únosnost bodová: 0.5 kg
SDK SVISLA CAST PODHLEDU | Půdorys 1.PP | SDK SVISLA CAST PODHLEDU 0.04 m |  | SDK SVISLA CAST PODHLEDU |  | 1364HWa0798562090 | m3 | Celá stěna | Nový | Suché stavební práce | SDK SVISLA CAST PODHLEDU | no | 1364Stě0798562091 | m3 | Stěna |  | 0.04 | 0.495 | 0.495 | 0.02 | 4.95 | 0.02 | 0.198 | 0.1 | NEMSOK - Object Layer Attributes #1, Kód prvku: PH01.02.0013; Object Layer Attributes #1, Požární odolnost: bez požadavku; Object Layer Attributes #1, Statická funkce: Ne; Object Layer Attributes #1, Výška svěšení: 0.35 m; Object Layer Attributes #1, Únosnost bodová: 0.5 kg
SDK SVISLA CAST PODHLEDU | Půdorys 1.PP | SDK SVISLA CAST PODHLEDU 0.04 m |  | SDK SVISLA CAST PODHLEDU |  | 1364HWa0798562118 | m3 | Celá stěna | Nový | Suché stavební práce | SDK SVISLA CAST PODHLEDU | no | 1364Stě0798562119 | m3 | Stěna |  | 0.04 | 0.27 | 0.27 | 0.011 | 0.9 | 0.011 | 0.036 | 0.3 | NEMSOK - Object Layer Attributes #1, Kód prvku: PH01.02.0014; Object Layer Attributes #1, Požární odolnost: bez požadavku; Object Layer Attributes #1, Statická funkce: Ne; Object Layer Attributes #1, Výška svěšení: 0.55 m; Object Layer Attributes #1, Únosnost bodová: 0.5 kg
SDK SVISLA CAST PODHLEDU | Půdorys 1.PP | SDK SVISLA CAST PODHLEDU 0.04 m |  | SDK SVISLA CAST PODHLEDU |  | 1364HWa0798562124 | m3 | Celá stěna | Nový | Suché stavební práce | SDK SVISLA CAST PODHLEDU | no | 1364Stě0798562125 | m3 | Stěna |  | 0.04 | 0.345 | 0.345 | 0.014 | 3.45 | 0.014 | 0.138 | 0.1 | NEMSOK - Object Layer Attributes #1, Kód prvku: PH01.02.0015; Object Layer Attributes #1, Požární odolnost: bez požadavku; Object Layer Attributes #1, Statická funkce: Ne; Object Layer Attributes #1, Výška svěšení: 0.35 m; Object Layer Attributes #1, Únosnost bodová: 0.5 kg
SDK SVISLA CAST PODHLEDU | Půdorys 1.PP | SDK SVISLA CAST PODHLEDU 0.04 m |  | SDK SVISLA CAST PODHLEDU |  | 1364HWa0798562134 | m3 | Celá stěna | Nový | Suché stavební práce | SDK SVISLA CAST PODHLEDU | no | 1364Stě0798562135 | m3 | Stěna |  | 0.04 | 0.33 | 0.33 | 0.013 | 3.3 | 0.013 | 0.132 | 0.1 | NEMSOK - Object Layer Attributes #1, Kód prvku: PH01.02.0016; Object Layer Attributes #1, Požární odolnost: bez požadavku; Object Layer Attributes #1, Statická funkce: Ne; Object Layer Attributes #1, Výška svěšení: 0.35 m; Object Layer Attributes #1, Únosnost bodová: 0.5 kg
SDK SVISLA CAST PODHLEDU | Půdorys 1.PP | SDK SVISLA CAST PODHLEDU 0.04 m |  | SDK SVISLA CAST PODHLEDU |  | 1364HWa0798562145 | m3 | Celá stěna | Nový | Suché stavební práce | SDK SVISLA CAST PODHLEDU | no | 1364Stě0798562146 | m3 | Stěna |  | 0.04 | 0.315 | 0.315 | 0.013 | 3.15 | 0.013 | 0.126 | 0.1 | NEMSOK - Object Layer Attributes #1, Kód prvku: PH01.02.0017; Object Layer Attributes #1, Požární odolnost: bez požadavku; Object Layer Attributes #1, Statická funkce: Ne; Object Layer Attributes #1, Výška svěšení: 0.35 m; Object Layer Attributes #1, Únosnost bodová: 0.5 kg
SDK SVISLA CAST PODHLEDU | Půdorys 1.PP | SDK SVISLA CAST PODHLEDU 0.04 m |  | SDK SVISLA CAST PODHLEDU |  | 1364HWa0798562160 | m3 | Celá stěna | Nový | Suché stavební práce | SDK SVISLA CAST PODHLEDU | no | 1364Stě0798562161 | m3 | Stěna |  | 0.04 | 0.4 | 0.4 | 0.016 | 4 | 0.016 | 0.16 | 0.1 | NEMSOK - Object Layer Attributes #1, Kód prvku: PH01.02.0018; Object Layer Attributes #1, Požární odolnost: bez požadavku; Object Layer Attributes #1, Statická funkce: Ne; Object Layer Attributes #1, Výška svěšení: 0.35 m; Object Layer Attributes #1, Únosnost bodová: 0.5 kg
SDK SVISLA CAST PODHLEDU | Půdorys 1.PP | SDK SVISLA CAST PODHLEDU 0.04 m |  | SDK SVISLA CAST PODHLEDU |  | 1364HWa0798562243 | m3 | Celá stěna | Nový | Suché stavební práce | SDK SVISLA CAST PODHLEDU | no | 1364Stě0798562244 | m3 | Stěna |  | 0.04 | 0.393 | 0.393 | 0.016 | 3.925 | 0.016 | 0.157 | 0.1 | NEMSOK - Object Layer Attributes #1, Kód prvku: PH01.02.0019; Object Layer Attributes #1, Požární odolnost: bez požadavku; Object Layer Attributes #1, Statická funkce: Ne; Object Layer Attributes #1, Výška svěšení: 0.35 m; Object Layer Attributes #1, Únosnost bodová: 0.5 kg
SDK SVISLA CAST PODHLEDU | Půdorys 1.PP | SDK SVISLA CAST PODHLEDU 0.04 m |  | SDK SVISLA CAST PODHLEDU |  | 1364HWa0798562258 | m3 | Celá stěna | Nový | Suché stavební práce | SDK SVISLA CAST PODHLEDU | no | 1364Stě0798562259 | m3 | Stěna |  | 0.04 | 0.392 | 0.393 | 0.016 | 3.925 | 0.016 | 0.157 | 0.1 | NEMSOK - Object Layer Attributes #1, Kód prvku: PH01.02.0020; Object Layer Attributes #1, Požární odolnost: bez požadavku; Object Layer Attributes #1, Statická funkce: Ne; Object Layer Attributes #1, Výška svěšení: 0.35 m; Object Layer Attributes #1, Únosnost bodová: 0.5 kg
YTONG 100 | Půdorys 1.PP | YTONG 100 0.1 m |  | YTONG 100 |  | 1364HWa0798584674 | m3 | Celá stěna | Nový | Zednické práce | YTONG 100 | no | 1364Stě0798584675 | m3 | Stěna |  | 0.1 | 1.449 | 1.16 | 0.145 | 1.525 | 0.116 | 0.152 | 0.95 | NEMSOK - Object Layer Attributes #1, Kód prvku: SN06.02.1022; Object Layer Attributes #1, Funkce: Ne; Object Layer Attributes #1, U-hodnota: 1.111; Object Layer Attributes #1, Podlaží: 1.PP; Object Layer Attributes #1, Neprůzvučnost: 35 dB; Object Layer Attributes #1, Požární odolnost: EI 120; Object Layer Attributes #1, Pevnost zdiva: 1,92 N/mm2; Object Layer Attributes #1, Funkce (venkovní): Ne; Object Layer Attributes #1, Statická funkce: Ne
SDK SVISLA CAST PODHLEDU | Půdorys 1.PP | SDK SVISLA CAST PODHLEDU 0.04 m |  | SDK SVISLA CAST PODHLEDU |  | 1364HWa0798593325 | m3 | Celá stěna | Nový | Suché stavební práce | SDK SVISLA CAST PODHLEDU | no | 1364Stě0798593326 | m3 | Stěna |  | 0.04 | 1.733 | 1.733 | 0.069 | 3.85 | 0.069 | 0.154 | 0.45 | NEMSOK - Object Layer Attributes #1, Kód prvku: PH01.02.0021; Object Layer Attributes #1, Požární odolnost: bez požadavku; Object Layer Attributes #1, Statická funkce: Ne; Object Layer Attributes #1, Výška svěšení: 0.45 m; Object Layer Attributes #1, Únosnost bodová: 0.5 kg
SDK SVISLA CAST PODHLEDU | Půdorys 1.PP | SDK SVISLA CAST PODHLEDU 0.04 m |  | SDK SVISLA CAST PODHLEDU |  | 1364HWa0798593332 | m3 | Celá stěna | Nový | Suché stavební práce | SDK SVISLA CAST PODHLEDU | no | 1364Stě0798593333 | m3 | Stěna |  | 0.04 | 2.047 | 2.048 | 0.082 | 4.55 | 0.082 | 0.182 | 0.45 | NEMSOK - Object Layer Attributes #1, Kód prvku: PH01.02.0022; Object Layer Attributes #1, Požární odolnost: bez požadavku; Object Layer Attributes #1, Statická funkce: Ne; Object Layer Attributes #1, Výška svěšení: 0.45 m; Object Layer Attributes #1, Únosnost bodová: 0.5 kg
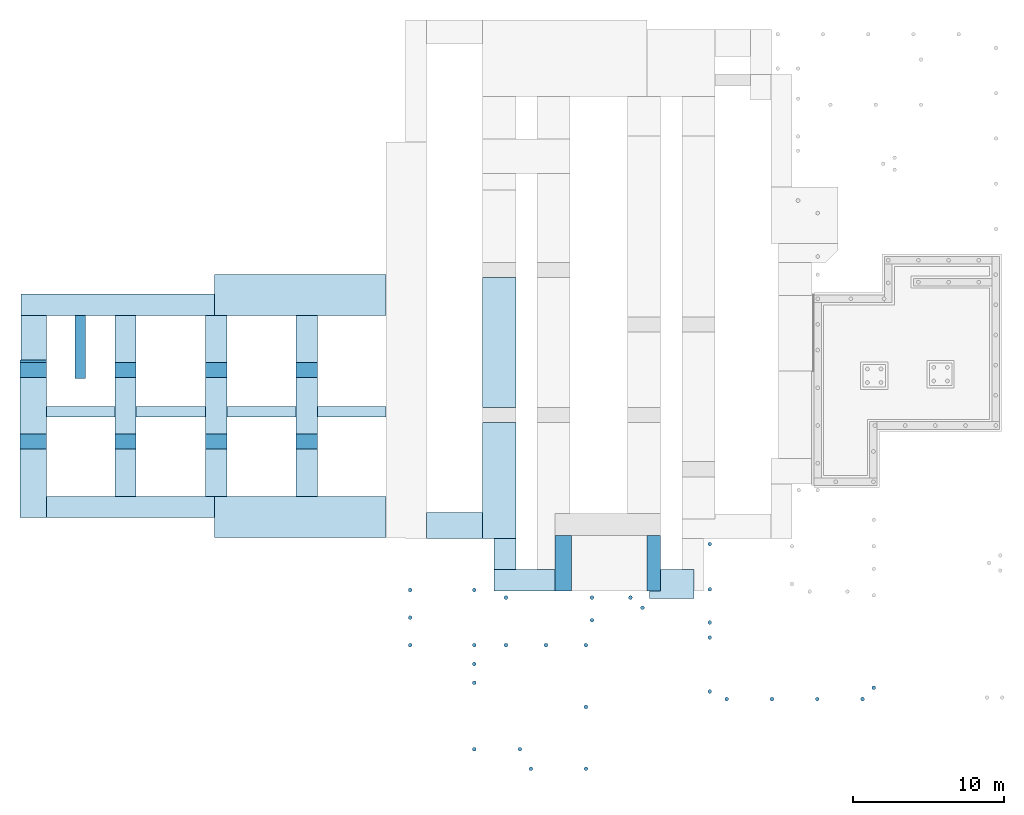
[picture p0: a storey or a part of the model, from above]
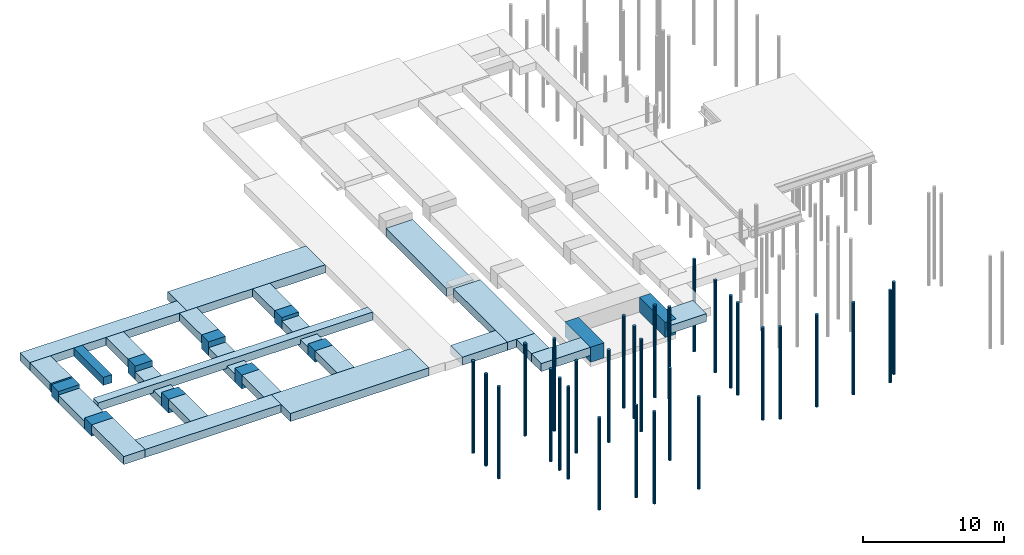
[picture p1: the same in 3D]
Properties of the parts of a building model (IFC4), part 29 of 45

# IfcWall (2385)
Name | In | Material | Faktor | Označení | Požární odolnost | Allright_Stavebni_dil_ID | Jednotka | Název_objektu | Object Layer Attributes #1, Status | Object Layer Attributes #1, Práce | Object Layer Attributes #1, Materiál | Object Layer Attributes #1, Staticky nosná konstrukce | Object Layer Attributes #1, Allright_Stavebni_dil_ID | Object Layer Attributes #1, Jednotka | Object Layer Attributes #1, Název_objektu | ThermalTransmittance (W/K/m2) | Width (m) | GrossSideArea (m2) | NetSideArea (m2) | GrossVolume (m3) | Length (m) | NetVolume (m3) | GrossFootprintArea (m2) | Height (m)
ZDIVO Z CDm | Půdorys 1.PP | ZDIVO Z CDm 0.125 m |  | ZDIVO Z CDm | A | 1364HWa0798605888 | m3 | Celá stěna | Bouraný | Zednické práce | ZDIVO Z CDm |  | 1364Stě0798605891 | m3 | Stěna | 0 | 0.125 | 2.12 | 0 | 0.265 | 1 | 0 | 0.125 | 2.12
ZDIVO Z CDm | Půdorys 1.PP | ZDIVO Z CDm 0.125 m |  | ZDIVO Z CDm | A | 1364HWa0798605892 | m3 | Celá stěna | Bouraný | Zednické práce | ZDIVO Z CDm | yes | 1364Stě0798605902 | m3 | Stěna | 0 | 0.125 | 2.544 | 0.12 | 0.318 | 1.2 | 0.015 | 0.15 | 2.12 | NEMSOK - Object Layer Attributes #1, Statická funkce: Ano
ZDIVO Z CDm | Půdorys 1.PP | ZDIVO Z CDm 0.125 m |  | ZDIVO Z CDm | A | 1364HWa0798606084 | m3 | Celá stěna | Bouraný | Zednické práce | ZDIVO Z CDm | yes | 1364Stě0798606085 | m3 | Stěna | 0 | 0.125 | 1.908 | 0.09 | 0.238 | 0.9 | 0.011 | 0.113 | 2.12 | NEMSOK - Object Layer Attributes #1, Statická funkce: Ano
ZDIVO Z CDm | Půdorys 1.PP | ZDIVO Z CDm 0.125 m |  | ZDIVO Z CDm | A | 1364HWa0798606462 | m3 | Celá stěna | Stávající | Zednické práce | ZDIVO Z CDm |  | 1364Stě0798606463 | m3 | Stěna | 0 | 0.125 | 2.424 | 0 | 0.303 | 1.2 | 0 | 0.15 | 2.02
ZDIVO Z CDm | Půdorys 1.PP | ZDIVO Z CDm 0.125 m |  | ZDIVO Z CDm | A | 1364HWa0798606510 | m3 | Celá stěna | Stávající | Zednické práce | ZDIVO Z CDm |  | 1364Stě0798606511 | m3 | Stěna | 0 | 0.125 | 1.696 | 0 | 0.212 | 0.8 | 0 | 0.1 | 2.12
ZDIVO Z CDm | Půdorys 1.PP | ZDIVO Z CDm 0.125 m |  | ZDIVO Z CDm | A | 1364HWa0798606537 | m3 | Celá stěna | Stávající | Zednické práce | ZDIVO Z CDm |  | 1364Stě0798606538 | m3 | Stěna | 0 | 0.125 | 2.544 | 0 | 0.318 | 1.2 | 0 | 0.15 | 2.12
SDK SVISLA CAST PODHLEDU | Půdorys 1.PP | SDK SVISLA CAST PODHLEDU 0.04 m |  | SDK SVISLA CAST PODHLEDU | bez požadavku | 1364HWa0798607118 | m3 | Celá stěna | Nový | Suché stavební práce | SDK SVISLA CAST PODHLEDU | no | 1364Stě0798607117 | m3 | Stěna |  | 0.04 | 0.36 | 0.36 | 0.014 | 1.2 | 0.014 | 0.048 | 0.3 | NEMSOK - Object Layer Attributes #1, Kód prvku: PH01.02.0023; Object Layer Attributes #1, Požární odolnost: bez požadavku; Object Layer Attributes #1, Statická funkce: Ne; Object Layer Attributes #1, Výška svěšení: 0.5 m; Object Layer Attributes #1, Únosnost bodová: 0.5 kg
ZELEZOBETONOVÁ KCE | Půdorys 1.PP | ZELEZOBETONOVÁ KCE 0.2 m, LIGNOPOR 0.025 m, PÓROBETONOVÉ ZDIVO 0.08 m | 1 | ZELEZOBETONOVÁ KCE | A | 1364HWa0798607181 | m3 | Celá stěna | Stávající | Betonářské práce | ZELEZOBETONOVÁ KCE |  | 1364Stě0798607182 | m3 | Stěna | 0 | 0.305 | 1.35 | 0 | 0.412 | 0.9 | 0 | 0.274 | 1.5 | NEMSOK - Object Layer Attributes #2, 2D interakce: yes; Object Layer Attributes #2, Status: Stávající; Object Layer Attributes #2, Práce: Zateplovací systémy; Object Layer Attributes #2, Materiál: LIGNOPOR; Object Layer Attributes #2, Allright_Stavebni_dil_ID: 1364Stě0798607183; Object Layer Attributes #2, Jednotka: m3; Object Layer Attributes #2, Název_objektu: Stěna; Object Layer Attributes #3, 2D interakce: yes; Object Layer Attributes #3, Status: Stávající; Object Layer Attributes #3, Práce: Zednické práce; Object Layer Attributes #3, Materiál: PÓROBETONOVÉ ZDIVO; Object Layer Attributes #3, Allright_Stavebni_dil_ID: 1364Stě0798607184; Object Layer Attributes #3, Jednotka: m3; Object Layer Attributes #3, Název_objektu: Stěna; Statická funkce: Ano; Pset_WallCommon - LoadBearing: yes
ZELEZOBETONOVÁ KCE | Půdorys 1.PP | ZELEZOBETONOVÁ KCE 0.2 m, LIGNOPOR 0.025 m, PÓROBETONOVÉ ZDIVO 0.08 m | 1 | ZELEZOBETONOVÁ KCE | A | 1364HWa0798607159 | m3 | Celá stěna | Stávající | Betonářské práce | ZELEZOBETONOVÁ KCE |  | 1364Stě0798607160 | m3 | Stěna | 0 | 0.305 | 1.35 | 0 | 0.412 | 0.9 | 0 | 0.274 | 1.5 | NEMSOK - Object Layer Attributes #2, 2D interakce: yes; Object Layer Attributes #2, Status: Stávající; Object Layer Attributes #2, Práce: Zateplovací systémy; Object Layer Attributes #2, Materiál: LIGNOPOR; Object Layer Attributes #2, Allright_Stavebni_dil_ID: 1364Stě0798607161; Object Layer Attributes #2, Jednotka: m3; Object Layer Attributes #2, Název_objektu: Stěna; Object Layer Attributes #3, 2D interakce: yes; Object Layer Attributes #3, Status: Stávající; Object Layer Attributes #3, Práce: Zednické práce; Object Layer Attributes #3, Materiál: PÓROBETONOVÉ ZDIVO; Object Layer Attributes #3, Allright_Stavebni_dil_ID: 1364Stě0798607162; Object Layer Attributes #3, Jednotka: m3; Object Layer Attributes #3, Název_objektu: Stěna; Statická funkce: Ano; Pset_WallCommon - LoadBearing: yes
ZELEZOBETONOVÁ KCE | Půdorys 1.PP | ZELEZOBETONOVÁ KCE 0.2 m, LIGNOPOR 0.025 m, PÓROBETONOVÉ ZDIVO 0.08 m | 1 | ZELEZOBETONOVÁ KCE | A | 1364HWa0798607170 | m3 | Celá stěna | Stávající | Betonářské práce | ZELEZOBETONOVÁ KCE |  | 1364Stě0798607171 | m3 | Stěna | 0 | 0.305 | 1.35 | 0 | 0.412 | 0.9 | 0 | 0.274 | 1.5 | NEMSOK - Object Layer Attributes #2, 2D interakce: yes; Object Layer Attributes #2, Status: Stávající; Object Layer Attributes #2, Práce: Zateplovací systémy; Object Layer Attributes #2, Materiál: LIGNOPOR; Object Layer Attributes #2, Allright_Stavebni_dil_ID: 1364Stě0798607172; Object Layer Attributes #2, Jednotka: m3; Object Layer Attributes #2, Název_objektu: Stěna; Object Layer Attributes #3, 2D interakce: yes; Object Layer Attributes #3, Status: Stávající; Object Layer Attributes #3, Práce: Zednické práce; Object Layer Attributes #3, Materiál: PÓROBETONOVÉ ZDIVO; Object Layer Attributes #3, Allright_Stavebni_dil_ID: 1364Stě0798607173; Object Layer Attributes #3, Jednotka: m3; Object Layer Attributes #3, Název_objektu: Stěna; Statická funkce: Ano; Pset_WallCommon - LoadBearing: yes
ZDIVO Z CDm | Půdorys 1.PP | ZDIVO Z CDm 0.125 m |  | ZDIVO Z CDm | A | 1364HWa0798609470 | m3 | Celá stěna | Stávající | Zednické práce | ZDIVO Z CDm | yes | 1364Stě0798609471 | m3 | Stěna | 0 | 0.125 | 3.286 | 0 | 0.411 | 1.55 | 0 | 0.194 | 2.12
SDK - 1 KCE + DVOJITÉ OPLÁŠTĚNÍ | Půdorys 1.PP | SDK - 1 KCE + DVOJITÉ OPLÁŠTĚNÍ 0.15 m |  | SDK - 1 KCE + DVOJITÉ OPLÁŠTĚNÍ |  | 1364HWa0000000146 | m3 | Celá stěna | Nový | Suché stavební práce | SDK - 1 KCE + DVOJITÉ OPLÁŠTĚNÍ | no | 1364Stě0000000147 | m3 | Stěna |  | 0.15 | 14.945 | 12.711 | 2.242 | 4.9 | 1.907 | 0.735 | 3.05 | NEMSOK - Object Layer Attributes #1, Kód prvku: SN07.02.0001; Object Layer Attributes #1, Podlaží: 1.PP; Object Layer Attributes #1, Požární odolnost: EI 60; Object Layer Attributes #1, Funkce (venkovní): Ne; Object Layer Attributes #1, Statická funkce: Ne; Object Layer Attributes #1, Vážená stavební neprůzvučnost: 54; Object Layer Attributes #1, Vlhkostní namáhání oboustranné: Ne; Object Layer Attributes #1, Tloušťka opláštění: 2×12,5; Object Layer Attributes #1, Typ SDK desky: vysokopevnostní+bílá; Object Layer Attributes #1, Způsob opláštění: Oboustranné; Object Layer Attributes #1, Tloušťka izolace (2): 100; Object Layer Attributes #1, Objemová hmotnost izolace: 25; Object Layer Attributes #1, Typ profilu pro SDK: CW 100; Object Layer Attributes #1, Rozteč rastru: 625
SDK BARYT - 1 KCE + DVOJITÉ OPLÁ | Půdorys 1.PP | SDK BARYT - 1 KCE + DVOJITÉ OPLÁ 0.15 m |  | SDK BARYT - 1 KCE + DVOJITÉ OPLÁ |  | 1364HWa0000002597 | m3 | Celá stěna | Nový | Suché stavební práce | SDK BARYT - 1 KCE + DVOJITÉ OPLÁ | no | 1364Stě0000002598 | m3 | Stěna |  | 0.15 | 20.054 | 15.235 | 3.008 | 6.575 | 2.285 | 0.986 | 3.05 | NEMSOK - Object Layer Attributes #1, Kód prvku: SN07.02.0001; Object Layer Attributes #1, Podlaží: 1.PP; Object Layer Attributes #1, Požární odolnost: EI 60; Object Layer Attributes #1, Funkce (venkovní): Ne; Object Layer Attributes #1, Statická funkce: Ne; Object Layer Attributes #1, Vážená stavební neprůzvučnost: 54; Object Layer Attributes #1, Vlhkostní namáhání oboustranné: Ne; Object Layer Attributes #1, Tloušťka opláštění: 2×12,5; Object Layer Attributes #1, Typ SDK desky: s obsahem síranu barnatého; Object Layer Attributes #1, Způsob opláštění: Oboustranné; Object Layer Attributes #1, Tloušťka izolace (2): 100; Object Layer Attributes #1, Objemová hmotnost izolace: 25; Object Layer Attributes #1, Typ profilu pro SDK: CW 100; Object Layer Attributes #1, Rozteč rastru: 625
SDK - 1 KCE + DVOJITÉ OPLÁŠTĚNÍ | Půdorys 1.PP | SDK - 1 KCE + DVOJITÉ OPLÁŠTĚNÍ 0.15 m |  | SDK - 1 KCE + DVOJITÉ OPLÁŠTĚNÍ |  | 1364HWa0000002612 | m3 | Celá stěna | Nový | Suché stavební práce | SDK - 1 KCE + DVOJITÉ OPLÁŠTĚNÍ | no | 1364Stě0000002613 | m3 | Stěna |  | 0.15 | 16.47 | 11.313 | 2.471 | 5.4 | 1.697 | 0.81 | 3.05 | NEMSOK - Object Layer Attributes #1, Kód prvku: SN07.02.0001; Object Layer Attributes #1, Podlaží: 1.PP; Object Layer Attributes #1, Požární odolnost: EI 60; Object Layer Attributes #1, Funkce (venkovní): Ne; Object Layer Attributes #1, Statická funkce: Ne; Object Layer Attributes #1, Vážená stavební neprůzvučnost: 54; Object Layer Attributes #1, Vlhkostní namáhání oboustranné: Ne; Object Layer Attributes #1, Tloušťka opláštění: 2×12,5; Object Layer Attributes #1, Typ SDK desky: vysokopevnostní+bílá; Object Layer Attributes #1, Způsob opláštění: Oboustranné; Object Layer Attributes #1, Tloušťka izolace (2): 100; Object Layer Attributes #1, Objemová hmotnost izolace: 25; Object Layer Attributes #1, Typ profilu pro SDK: CW 100; Object Layer Attributes #1, Rozteč rastru: 625
SDK - 1 KCE + DVOJITÉ OPLÁŠTĚNÍ | Půdorys 1.PP | SDK - 1 KCE + DVOJITÉ OPLÁŠTĚNÍ 0.125 m |  | SDK - 1 KCE + DVOJITÉ OPLÁŠTĚNÍ |  | 1364HWa0000002617 | m3 | Celá stěna | Nový | Suché stavební práce | SDK - 1 KCE + DVOJITÉ OPLÁŠTĚNÍ | no | 1364Stě0000002618 | m3 | Stěna |  | 0.125 | 13.42 | 11.19 | 1.677 | 4.4 | 1.399 | 0.55 | 3.05 | NEMSOK - Object Layer Attributes #1, Kód prvku: SN07.02.0001; Object Layer Attributes #1, Podlaží: 1.PP; Object Layer Attributes #1, Požární odolnost: EI 60; Object Layer Attributes #1, Funkce (venkovní): Ne; Object Layer Attributes #1, Statická funkce: Ne; Object Layer Attributes #1, Vážená stavební neprůzvučnost: 54; Object Layer Attributes #1, Vlhkostní namáhání oboustranné: Ne; Object Layer Attributes #1, Tloušťka opláštění: 2×12,5; Object Layer Attributes #1, Typ SDK desky: vysokopevnostní+bílá; Object Layer Attributes #1, Způsob opláštění: Oboustranné; Object Layer Attributes #1, Tloušťka izolace (2): 75; Object Layer Attributes #1, Objemová hmotnost izolace: 25; Object Layer Attributes #1, Typ profilu pro SDK: CW 75; Object Layer Attributes #1, Rozteč rastru: 625
SDK - 1 KCE + DVOJITÉ OPLÁŠTĚNÍ | Půdorys 1.PP | SDK - 1 KCE + DVOJITÉ OPLÁŠTĚNÍ 0.125 m |  | SDK - 1 KCE + DVOJITÉ OPLÁŠTĚNÍ |  | 1364HWa0000002627 | m3 | Celá stěna | Nový | Suché stavební práce | SDK - 1 KCE + DVOJITÉ OPLÁŠTĚNÍ | no | 1364Stě0000002628 | m3 | Stěna |  | 0.125 | 11.895 | 11.815 | 1.487 | 3.9 | 1.477 | 0.487 | 3.05 | NEMSOK - Object Layer Attributes #1, Kód prvku: SN07.02.0001; Object Layer Attributes #1, Podlaží: 1.PP; Object Layer Attributes #1, Požární odolnost: EI 60; Object Layer Attributes #1, Funkce (venkovní): Ne; Object Layer Attributes #1, Statická funkce: Ne; Object Layer Attributes #1, Vážená stavební neprůzvučnost: 54; Object Layer Attributes #1, Vlhkostní namáhání oboustranné: Ne; Object Layer Attributes #1, Tloušťka opláštění: 2×12,5; Object Layer Attributes #1, Typ SDK desky: vysokopevnostní+bílá; Object Layer Attributes #1, Způsob opláštění: Oboustranné; Object Layer Attributes #1, Tloušťka izolace (2): 75; Object Layer Attributes #1, Objemová hmotnost izolace: 25; Object Layer Attributes #1, Typ profilu pro SDK: CW 75; Object Layer Attributes #1, Rozteč rastru: 625
SDK - 1 KCE + DVOJITÉ OPLÁŠTĚNÍ | Půdorys 1.PP | SDK - 1 KCE + DVOJITÉ OPLÁŠTĚNÍ 0.1 m |  | SDK - 1 KCE + DVOJITÉ OPLÁŠTĚNÍ |  | 1364HWa0000002637 | m3 | Celá stěna | Nový | Suché stavební práce | SDK - 1 KCE + DVOJITÉ OPLÁŠTĚNÍ | no | 1364Stě0000002638 | m3 | Stěna |  | 0.1 | 3.965 | 2.269 | 0.397 | 1.3 | 0.227 | 0.13 | 3.05 | NEMSOK - Object Layer Attributes #1, Kód prvku: SN07.02.0001; Object Layer Attributes #1, Podlaží: 1.PP; Object Layer Attributes #1, Požární odolnost: EI 60; Object Layer Attributes #1, Funkce (venkovní): Ne; Object Layer Attributes #1, Statická funkce: Ne; Object Layer Attributes #1, Vážená stavební neprůzvučnost: 54; Object Layer Attributes #1, Vlhkostní namáhání oboustranné: Ne; Object Layer Attributes #1, Tloušťka opláštění: 2×12,5; Object Layer Attributes #1, Typ SDK desky: vysokopevnostní+bílá; Object Layer Attributes #1, Způsob opláštění: Oboustranné; Object Layer Attributes #1, Tloušťka izolace (2): 50; Object Layer Attributes #1, Objemová hmotnost izolace: 25; Object Layer Attributes #1, Typ profilu pro SDK: CW 50; Object Layer Attributes #1, Rozteč rastru: 625
SDK BARYT - 1 KCE + DVOJITÉ OPLÁ | Půdorys 1.PP | SDK BARYT - 1 KCE + DVOJITÉ OPLÁ 0.15 m |  | SDK BARYT - 1 KCE + DVOJITÉ OPLÁ |  | 1364HWa0000007540 | m3 | Celá stěna | Nový | Suché stavební práce | SDK BARYT - 1 KCE + DVOJITÉ OPLÁ | no | 1364Stě0000007541 | m3 | Stěna |  | 0.15 | 20.359 | 20.226 | 3.054 | 6.675 | 3.034 | 1.001 | 3.05 | NEMSOK - Object Layer Attributes #1, Kód prvku: SN07.02.0001; Object Layer Attributes #1, Podlaží: 1.PP; Object Layer Attributes #1, Požární odolnost: EI 60; Object Layer Attributes #1, Funkce (venkovní): Ne; Object Layer Attributes #1, Statická funkce: Ne; Object Layer Attributes #1, Vážená stavební neprůzvučnost: 54; Object Layer Attributes #1, Vlhkostní namáhání oboustranné: Ne; Object Layer Attributes #1, Tloušťka opláštění: 2×12,5; Object Layer Attributes #1, Typ SDK desky: s obsahem síranu barnatého; Object Layer Attributes #1, Způsob opláštění: Oboustranné; Object Layer Attributes #1, Tloušťka izolace (2): 100; Object Layer Attributes #1, Objemová hmotnost izolace: 25; Object Layer Attributes #1, Typ profilu pro SDK: CW 100; Object Layer Attributes #1, Rozteč rastru: 625
SDK ŠACHTOVÁ STĚNA/SDK OPL. S PO | Půdorys 1.PP | SDK ŠACHTOVÁ STĚNA/SDK OPL. S PO 0.075 m |  | SDK ŠACHTOVÁ STĚNA/SDK OPL. S PO |  | 1364HWa0000007547 | m3 | Celá stěna | Nový | Suché stavební práce | SDK ŠACHTOVÁ STĚNA/SDK OPL. S PO | no | 1364Stě0000007548 | m3 | Stěna |  | 0.075 | 0.516 | 0.516 | 0.039 | 0.175 | 0.039 | 0.013 | 2.95 | NEMSOK - Object Layer Attributes #1, Kód prvku: SN07.02.0001; Object Layer Attributes #1, Podlaží: 1.PP; Object Layer Attributes #1, Požární odolnost: bez požadavku; Object Layer Attributes #1, Funkce (venkovní): Ne; Object Layer Attributes #1, Statická funkce: Ne; Object Layer Attributes #1, Vlhkostní namáhání oboustranné: Ne; Object Layer Attributes #1, Tloušťka opláštění: 2×12,5; Object Layer Attributes #1, Typ SDK desky: vysokopevnostní+bílá; Object Layer Attributes #1, Způsob opláštění: Jednostranné; Object Layer Attributes #1, Tloušťka izolace (2): 0; Object Layer Attributes #1, Objemová hmotnost izolace: 0; Object Layer Attributes #1, Typ profilu pro SDK: CW 50; Object Layer Attributes #1, Rozteč rastru: 625
SDK - 1 KCE + DVOJITÉ OPLÁŠTĚNÍ | Půdorys 1.PP | SDK - 1 KCE + DVOJITÉ OPLÁŠTĚNÍ 0.125 m |  | SDK - 1 KCE + DVOJITÉ OPLÁŠTĚNÍ |  | 1364HWa0000007644 | m3 | Celá stěna | Nový | Suché stavební práce | SDK - 1 KCE + DVOJITÉ OPLÁŠTĚNÍ | no | 1364Stě0000007645 | m3 | Stěna |  | 0.125 | 40.184 | 27.232 | 5.023 | 13.175 | 3.541 | 1.647 | 3.05 | NEMSOK - Object Layer Attributes #1, Kód prvku: SN07.02.0001; Object Layer Attributes #1, Podlaží: 1.PP; Object Layer Attributes #1, Požární odolnost: EI 60; Object Layer Attributes #1, Funkce (venkovní): Ne; Object Layer Attributes #1, Statická funkce: Ne; Object Layer Attributes #1, Vážená stavební neprůzvučnost: 54; Object Layer Attributes #1, Vlhkostní namáhání oboustranné: Ne; Object Layer Attributes #1, Tloušťka opláštění: 2×12,5; Object Layer Attributes #1, Typ SDK desky: vysokopevnostní+bílá; Object Layer Attributes #1, Způsob opláštění: Oboustranné; Object Layer Attributes #1, Tloušťka izolace (2): 75; Object Layer Attributes #1, Objemová hmotnost izolace: 25; Object Layer Attributes #1, Typ profilu pro SDK: CW 75; Object Layer Attributes #1, Rozteč rastru: 625
SDK - 1 KCE + DVOJITÉ OPLÁŠTĚNÍ | Půdorys 1.PP | SDK - 1 KCE + DVOJITÉ OPLÁŠTĚNÍ 0.125 m |  | SDK - 1 KCE + DVOJITÉ OPLÁŠTĚNÍ |  | 1364HWa0000007664 | m3 | Celá stěna | Nový | Suché stavební práce | SDK - 1 KCE + DVOJITÉ OPLÁŠTĚNÍ | no | 1364Stě0000007665 | m3 | Stěna |  | 0.125 | 13.42 | 10.766 | 1.678 | 4.4 | 1.308 | 0.55 | 3.05 | NEMSOK - Object Layer Attributes #1, Kód prvku: SN07.02.0001; Object Layer Attributes #1, Podlaží: 1.PP; Object Layer Attributes #1, Požární odolnost: EI 60; Object Layer Attributes #1, Funkce (venkovní): Ne; Object Layer Attributes #1, Statická funkce: Ne; Object Layer Attributes #1, Vážená stavební neprůzvučnost: 54; Object Layer Attributes #1, Vlhkostní namáhání oboustranné: Ne; Object Layer Attributes #1, Tloušťka opláštění: 2×12,5; Object Layer Attributes #1, Typ SDK desky: vysokopevnostní+bílá; Object Layer Attributes #1, Způsob opláštění: Oboustranné; Object Layer Attributes #1, Tloušťka izolace (2): 75; Object Layer Attributes #1, Objemová hmotnost izolace: 25; Object Layer Attributes #1, Typ profilu pro SDK: CW 75; Object Layer Attributes #1, Rozteč rastru: 625
SDK ŠACHTOVÁ STĚNA/SDK OPL. S PO | Půdorys 1.PP | SDK ŠACHTOVÁ STĚNA/SDK OPL. S PO 0.075 m |  | SDK ŠACHTOVÁ STĚNA/SDK OPL. S PO |  | 1364HWa0000007961 | m3 | Celá stěna | Nový | Suché stavební práce | SDK ŠACHTOVÁ STĚNA/SDK OPL. S PO | no | 1364Stě0000007962 | m3 | Stěna |  | 0.075 | 0.664 | 0.664 | 0.05 | 0.225 | 0.05 | 0.017 | 2.95 | NEMSOK - Object Layer Attributes #1, Kód prvku: SN07.02.0001; Object Layer Attributes #1, Podlaží: 1.PP; Object Layer Attributes #1, Požární odolnost: bez požadavku; Object Layer Attributes #1, Funkce (venkovní): Ne; Object Layer Attributes #1, Statická funkce: Ne; Object Layer Attributes #1, Vlhkostní namáhání oboustranné: Ne; Object Layer Attributes #1, Tloušťka opláštění: 2×12,5; Object Layer Attributes #1, Typ SDK desky: vysokopevnostní+bílá; Object Layer Attributes #1, Způsob opláštění: Jednostranné; Object Layer Attributes #1, Tloušťka izolace (2): 0; Object Layer Attributes #1, Objemová hmotnost izolace: 0; Object Layer Attributes #1, Typ profilu pro SDK: CW 50; Object Layer Attributes #1, Rozteč rastru: 625
SDK ŠACHTOVÁ STĚNA/SDK OPL. S PO | Půdorys 1.PP | SDK ŠACHTOVÁ STĚNA/SDK OPL. S PO 0.075 m |  | SDK ŠACHTOVÁ STĚNA/SDK OPL. S PO |  | 1364HWa0000007966 | m3 | Celá stěna | Nový | Suché stavební práce | SDK ŠACHTOVÁ STĚNA/SDK OPL. S PO | no | 1364Stě0000007967 | m3 | Stěna |  | 0.075 | 1.328 | 1.288 | 0.1 | 0.45 | 0.097 | 0.034 | 2.95 | NEMSOK - Object Layer Attributes #1, Kód prvku: SN07.02.0001; Object Layer Attributes #1, Podlaží: 1.PP; Object Layer Attributes #1, Požární odolnost: bez požadavku; Object Layer Attributes #1, Funkce (venkovní): Ne; Object Layer Attributes #1, Statická funkce: Ne; Object Layer Attributes #1, Vlhkostní namáhání oboustranné: Ne; Object Layer Attributes #1, Tloušťka opláštění: 2×12,5; Object Layer Attributes #1, Typ SDK desky: vysokopevnostní+bílá; Object Layer Attributes #1, Způsob opláštění: Jednostranné; Object Layer Attributes #1, Tloušťka izolace (2): 0; Object Layer Attributes #1, Objemová hmotnost izolace: 0; Object Layer Attributes #1, Typ profilu pro SDK: CW 50; Object Layer Attributes #1, Rozteč rastru: 625
SDK ŠACHTOVÁ STĚNA/SDK OPL. S PO | Půdorys 1.PP | SDK ŠACHTOVÁ STĚNA/SDK OPL. S PO 0.075 m |  | SDK ŠACHTOVÁ STĚNA/SDK OPL. S PO |  | 1364HWa0000007976 | m3 | Celá stěna | Nový | Suché stavební práce | SDK ŠACHTOVÁ STĚNA/SDK OPL. S PO | no | 1364Stě0000007977 | m3 | Stěna |  | 0.075 | 0.664 | 0.664 | 0.05 | 0.225 | 0.05 | 0.017 | 2.95 | NEMSOK - Object Layer Attributes #1, Kód prvku: SN07.02.0001; Object Layer Attributes #1, Podlaží: 1.PP; Object Layer Attributes #1, Požární odolnost: bez požadavku; Object Layer Attributes #1, Funkce (venkovní): Ne; Object Layer Attributes #1, Statická funkce: Ne; Object Layer Attributes #1, Vlhkostní namáhání oboustranné: Ne; Object Layer Attributes #1, Tloušťka opláštění: 2×12,5; Object Layer Attributes #1, Typ SDK desky: vysokopevnostní+bílá; Object Layer Attributes #1, Způsob opláštění: Jednostranné; Object Layer Attributes #1, Tloušťka izolace (2): 0; Object Layer Attributes #1, Objemová hmotnost izolace: 0; Object Layer Attributes #1, Typ profilu pro SDK: CW 50; Object Layer Attributes #1, Rozteč rastru: 625
SDK ŠACHTOVÁ STĚNA/SDK OPL. S PO | Půdorys 1.PP | SDK ŠACHTOVÁ STĚNA/SDK OPL. S PO 0.075 m |  | SDK ŠACHTOVÁ STĚNA/SDK OPL. S PO |  | 1364HWa0000007988 | m3 | Celá stěna | Nový | Suché stavební práce | SDK ŠACHTOVÁ STĚNA/SDK OPL. S PO | no | 1364Stě0000007995 | m3 | Stěna |  | 0.075 | 0.664 | 0.664 | 0.05 | 0.225 | 0.05 | 0.017 | 2.95 | NEMSOK - Object Layer Attributes #1, Kód prvku: SN07.02.0001; Object Layer Attributes #1, Podlaží: 1.PP; Object Layer Attributes #1, Požární odolnost: bez požadavku; Object Layer Attributes #1, Funkce (venkovní): Ne; Object Layer Attributes #1, Statická funkce: Ne; Object Layer Attributes #1, Vlhkostní namáhání oboustranné: Ne; Object Layer Attributes #1, Tloušťka opláštění: 2×12,5; Object Layer Attributes #1, Typ SDK desky: vysokopevnostní+bílá; Object Layer Attributes #1, Způsob opláštění: Jednostranné; Object Layer Attributes #1, Tloušťka izolace (2): 0; Object Layer Attributes #1, Objemová hmotnost izolace: 0; Object Layer Attributes #1, Typ profilu pro SDK: CW 50; Object Layer Attributes #1, Rozteč rastru: 625
SDK ŠACHTOVÁ STĚNA/SDK OPL. S PO | Půdorys 1.PP | SDK ŠACHTOVÁ STĚNA/SDK OPL. S PO 0.075 m |  | SDK ŠACHTOVÁ STĚNA/SDK OPL. S PO |  | 1364HWa0000007990 | m3 | Celá stěna | Nový | Suché stavební práce | SDK ŠACHTOVÁ STĚNA/SDK OPL. S PO | no | 1364Stě0000007993 | m3 | Stěna |  | 0.075 | 1.549 | 1.509 | 0.116 | 0.525 | 0.113 | 0.039 | 2.95 | NEMSOK - Object Layer Attributes #1, Kód prvku: SN07.02.0001; Object Layer Attributes #1, Podlaží: 1.PP; Object Layer Attributes #1, Požární odolnost: bez požadavku; Object Layer Attributes #1, Funkce (venkovní): Ne; Object Layer Attributes #1, Statická funkce: Ne; Object Layer Attributes #1, Vlhkostní namáhání oboustranné: Ne; Object Layer Attributes #1, Tloušťka opláštění: 2×12,5; Object Layer Attributes #1, Typ SDK desky: vysokopevnostní+bílá; Object Layer Attributes #1, Způsob opláštění: Jednostranné; Object Layer Attributes #1, Tloušťka izolace (2): 0; Object Layer Attributes #1, Objemová hmotnost izolace: 0; Object Layer Attributes #1, Typ profilu pro SDK: CW 50; Object Layer Attributes #1, Rozteč rastru: 625
SDK ŠACHTOVÁ STĚNA/SDK OPL. S PO | Půdorys 1.PP | SDK ŠACHTOVÁ STĚNA/SDK OPL. S PO 0.075 m |  | SDK ŠACHTOVÁ STĚNA/SDK OPL. S PO |  | 1364HWa0000007992 | m3 | Celá stěna | Nový | Suché stavební práce | SDK ŠACHTOVÁ STĚNA/SDK OPL. S PO | no | 1364Stě0000007994 | m3 | Stěna |  | 0.075 | 0.442 | 0.443 | 0.033 | 0.15 | 0.033 | 0.011 | 2.95 | NEMSOK - Object Layer Attributes #1, Kód prvku: SN07.02.0001; Object Layer Attributes #1, Podlaží: 1.PP; Object Layer Attributes #1, Požární odolnost: bez požadavku; Object Layer Attributes #1, Funkce (venkovní): Ne; Object Layer Attributes #1, Statická funkce: Ne; Object Layer Attributes #1, Vlhkostní namáhání oboustranné: Ne; Object Layer Attributes #1, Tloušťka opláštění: 2×12,5; Object Layer Attributes #1, Typ SDK desky: vysokopevnostní+bílá; Object Layer Attributes #1, Způsob opláštění: Jednostranné; Object Layer Attributes #1, Tloušťka izolace (2): 0; Object Layer Attributes #1, Objemová hmotnost izolace: 0; Object Layer Attributes #1, Typ profilu pro SDK: CW 50; Object Layer Attributes #1, Rozteč rastru: 625
SDK INSTAL. PŘDSTĚNA VYSOKÁ | Půdorys 1.PP | SDK INSTAL. PŘDSTĚNA VYSOKÁ 0.15 m |  | SDK INSTAL. PŘDSTĚNA VYSOKÁ | bez | 1364HWa0000008051 | m3 | Celá stěna | Nový | Suché stavební práce | SDK INSTAL. PŘDSTĚNA VYSOKÁ | no | 1364Stě0000008052 | m3 | Stěna |  | 0.15 | 5.49 | 5.49 | 0.824 | 1.8 | 0.824 | 0.27 | 3.05 | NEMSOK - Object Layer Attributes #1, Kód prvku: SN07.02.0001; Object Layer Attributes #1, Podlaží: 1.PP; Object Layer Attributes #1, Požární odolnost: bez požadavku; Object Layer Attributes #1, Funkce (venkovní): Ne; Podlaží: 1.PP; Object Layer Attributes #1, Statická funkce: Ne; Object Layer Attributes #1, Vlhkostní namáhání oboustranné: Ne; Object Layer Attributes #1, Tloušťka opláštění: 2×12,5; Object Layer Attributes #1, Typ SDK desky: impregnovaná; Object Layer Attributes #1, Způsob opláštění: Jednostranné; Object Layer Attributes #1, Tloušťka izolace (2): 0; Object Layer Attributes #1, Objemová hmotnost izolace: 0; Object Layer Attributes #1, Typ profilu pro SDK: CW 50; Object Layer Attributes #1, Rozteč rastru: 625; Funkce (venkovní): Ne; Vážená stavební neprůzvučnost: 0; Vlhkostní namáhání oboustranné: Ne; Tloušťka opláštění: 2×12,5; Typ SDK desky: vysokopevnostní+bílá; Způsob opláštění: Jednostranné; Tloušťka izolace (2): 100; Objemová hmotnost izolace: 25; Typ profilu pro SDK: ocelový; Rozteč rastru: 625
SDK OPL. PROFESÍ/SDK OPL. BEZ PO | Půdorys 1.PP | SDK OPL. PROFESÍ/SDK OPL. BEZ PO 0.075 m |  | SDK OPL. PROFESÍ/SDK OPL. BEZ PO |  | 1364HWa0000008067 | m3 | Celá stěna | Nový | Suché stavební práce | SDK OPL. PROFESÍ/SDK OPL. BEZ PO | no | 1364Stě0000008068 | m3 | Stěna |  | 0.075 | 1.22 | 1.22 | 0.092 | 0.4 | 0.092 | 0.03 | 3.05 | NEMSOK - Object Layer Attributes #1, Kód prvku: SN07.02.0001; Object Layer Attributes #1, Podlaží: 1.PP; Object Layer Attributes #1, Požární odolnost: bez požadavku; Object Layer Attributes #1, Funkce (venkovní): Ne; Object Layer Attributes #1, Statická funkce: Ne; Object Layer Attributes #1, Vlhkostní namáhání oboustranné: Ne; Object Layer Attributes #1, Tloušťka opláštění: 2×12,5; Object Layer Attributes #1, Typ SDK desky: impregnovaná; Object Layer Attributes #1, Způsob opláštění: Jednostranné; Object Layer Attributes #1, Tloušťka izolace (2): 0; Object Layer Attributes #1, Objemová hmotnost izolace: 0; Object Layer Attributes #1, Typ profilu pro SDK: CW 50; Object Layer Attributes #1, Rozteč rastru: 625
SDK OPL. PROFESÍ/SDK OPL. BEZ PO | Půdorys 1.PP | SDK OPL. PROFESÍ/SDK OPL. BEZ PO 0.075 m |  | SDK OPL. PROFESÍ/SDK OPL. BEZ PO |  | 1364HWa0000008077 | m3 | Celá stěna | Nový | Suché stavební práce | SDK OPL. PROFESÍ/SDK OPL. BEZ PO | no | 1364Stě0000008078 | m3 | Stěna |  | 0.075 | 0.915 | 0.915 | 0.069 | 0.3 | 0.069 | 0.022 | 3.05 | NEMSOK - Object Layer Attributes #1, Kód prvku: SN07.02.0001; Object Layer Attributes #1, Podlaží: 1.PP; Object Layer Attributes #1, Požární odolnost: bez požadavku; Object Layer Attributes #1, Funkce (venkovní): Ne; Object Layer Attributes #1, Statická funkce: Ne; Object Layer Attributes #1, Vlhkostní namáhání oboustranné: Ne; Object Layer Attributes #1, Tloušťka opláštění: 2×12,5; Object Layer Attributes #1, Typ SDK desky: impregnovaná; Object Layer Attributes #1, Způsob opláštění: Jednostranné; Object Layer Attributes #1, Tloušťka izolace (2): 0; Object Layer Attributes #1, Objemová hmotnost izolace: 0; Object Layer Attributes #1, Typ profilu pro SDK: CW 50; Object Layer Attributes #1, Rozteč rastru: 625
SDK ŠACHTOVÁ STĚNA/SDK OPL. S PO | Půdorys 1.PP | SDK ŠACHTOVÁ STĚNA/SDK OPL. S PO 0.075 m |  | SDK ŠACHTOVÁ STĚNA/SDK OPL. S PO |  | 1364HWa0000008134 | m3 | Celá stěna | Nový | Suché stavební práce | SDK ŠACHTOVÁ STĚNA/SDK OPL. S PO | no | 1364Stě0000008135 | m3 | Stěna |  | 0.075 | 1.106 | 1.066 | 0.083 | 0.375 | 0.08 | 0.028 | 2.95 | NEMSOK - Object Layer Attributes #1, Kód prvku: SN07.02.0001; Object Layer Attributes #1, Podlaží: 1.PP; Object Layer Attributes #1, Požární odolnost: bez požadavku; Object Layer Attributes #1, Funkce (venkovní): Ne; Object Layer Attributes #1, Statická funkce: Ne; Object Layer Attributes #1, Vlhkostní namáhání oboustranné: Ne; Object Layer Attributes #1, Tloušťka opláštění: 2×12,5; Object Layer Attributes #1, Typ SDK desky: vysokopevnostní+bílá; Object Layer Attributes #1, Způsob opláštění: Jednostranné; Object Layer Attributes #1, Tloušťka izolace (2): 0; Object Layer Attributes #1, Objemová hmotnost izolace: 0; Object Layer Attributes #1, Typ profilu pro SDK: CW 50; Object Layer Attributes #1, Rozteč rastru: 625
SDK ŠACHTOVÁ STĚNA/SDK OPL. S PO | Půdorys 1.PP | SDK ŠACHTOVÁ STĚNA/SDK OPL. S PO 0.075 m |  | SDK ŠACHTOVÁ STĚNA/SDK OPL. S PO |  | 1364HWa0000008139 | m3 | Celá stěna | Nový | Suché stavební práce | SDK ŠACHTOVÁ STĚNA/SDK OPL. S PO | no | 1364Stě0000008140 | m3 | Stěna |  | 0.075 | 0.885 | 0.885 | 0.066 | 0.3 | 0.066 | 0.022 | 2.95 | NEMSOK - Object Layer Attributes #1, Kód prvku: SN07.02.0001; Object Layer Attributes #1, Podlaží: 1.PP; Object Layer Attributes #1, Požární odolnost: bez požadavku; Object Layer Attributes #1, Funkce (venkovní): Ne; Object Layer Attributes #1, Statická funkce: Ne; Object Layer Attributes #1, Vlhkostní namáhání oboustranné: Ne; Object Layer Attributes #1, Tloušťka opláštění: 2×12,5; Object Layer Attributes #1, Typ SDK desky: vysokopevnostní+bílá; Object Layer Attributes #1, Způsob opláštění: Jednostranné; Object Layer Attributes #1, Tloušťka izolace (2): 0; Object Layer Attributes #1, Objemová hmotnost izolace: 0; Object Layer Attributes #1, Typ profilu pro SDK: CW 50; Object Layer Attributes #1, Rozteč rastru: 625
SDK ŠACHTOVÁ STĚNA/SDK OPL. S PO | Půdorys 1.PP | SDK ŠACHTOVÁ STĚNA/SDK OPL. S PO 0.075 m |  | SDK ŠACHTOVÁ STĚNA/SDK OPL. S PO |  | 1364HWa0000008171 | m3 | Celá stěna | Nový | Suché stavební práce | SDK ŠACHTOVÁ STĚNA/SDK OPL. S PO | no | 1364Stě0000008172 | m3 | Stěna |  | 0.075 | 0.885 | 0.885 | 0.066 | 0.3 | 0.066 | 0.023 | 2.95 | NEMSOK - Object Layer Attributes #1, Kód prvku: SN07.02.0001; Object Layer Attributes #1, Podlaží: 1.PP; Object Layer Attributes #1, Požární odolnost: bez požadavku; Object Layer Attributes #1, Funkce (venkovní): Ne; Object Layer Attributes #1, Statická funkce: Ne; Object Layer Attributes #1, Vlhkostní namáhání oboustranné: Ne; Object Layer Attributes #1, Tloušťka opláštění: 2×12,5; Object Layer Attributes #1, Typ SDK desky: vysokopevnostní+bílá; Object Layer Attributes #1, Způsob opláštění: Jednostranné; Object Layer Attributes #1, Tloušťka izolace (2): 0; Object Layer Attributes #1, Objemová hmotnost izolace: 0; Object Layer Attributes #1, Typ profilu pro SDK: CW 50; Object Layer Attributes #1, Rozteč rastru: 625
SDK ŠACHTOVÁ STĚNA/SDK OPL. S PO | Půdorys 1.PP | SDK ŠACHTOVÁ STĚNA/SDK OPL. S PO 0.075 m |  | SDK ŠACHTOVÁ STĚNA/SDK OPL. S PO |  | 1364HWa0000008176 | m3 | Celá stěna | Nový | Suché stavební práce | SDK ŠACHTOVÁ STĚNA/SDK OPL. S PO | no | 1364Stě0000008177 | m3 | Stěna |  | 0.075 | 1.18 | 0.98 | 0.089 | 0.4 | 0.074 | 0.03 | 2.95 | NEMSOK - Object Layer Attributes #1, Kód prvku: SN07.02.0001; Object Layer Attributes #1, Podlaží: 1.PP; Object Layer Attributes #1, Požární odolnost: bez požadavku; Object Layer Attributes #1, Funkce (venkovní): Ne; Object Layer Attributes #1, Statická funkce: Ne; Object Layer Attributes #1, Vlhkostní namáhání oboustranné: Ne; Object Layer Attributes #1, Tloušťka opláštění: 2×12,5; Object Layer Attributes #1, Typ SDK desky: vysokopevnostní+bílá; Object Layer Attributes #1, Způsob opláštění: Jednostranné; Object Layer Attributes #1, Tloušťka izolace (2): 0; Object Layer Attributes #1, Objemová hmotnost izolace: 0; Object Layer Attributes #1, Typ profilu pro SDK: CW 50; Object Layer Attributes #1, Rozteč rastru: 625
SDK ŠACHTOVÁ STĚNA/SDK OPL. S PO | Půdorys 1.PP | SDK ŠACHTOVÁ STĚNA/SDK OPL. S PO 0.075 m |  | SDK ŠACHTOVÁ STĚNA/SDK OPL. S PO |  | 1364HWa0000008186 | m3 | Celá stěna | Nový | Suché stavební práce | SDK ŠACHTOVÁ STĚNA/SDK OPL. S PO | no | 1364Stě0000008187 | m3 | Stěna |  | 0.075 | 0.885 | 0.885 | 0.066 | 0.3 | 0.066 | 0.023 | 2.95 | NEMSOK - Object Layer Attributes #1, Kód prvku: SN07.02.0001; Object Layer Attributes #1, Podlaží: 1.PP; Object Layer Attributes #1, Požární odolnost: bez požadavku; Object Layer Attributes #1, Funkce (venkovní): Ne; Object Layer Attributes #1, Statická funkce: Ne; Object Layer Attributes #1, Vlhkostní namáhání oboustranné: Ne; Object Layer Attributes #1, Tloušťka opláštění: 2×12,5; Object Layer Attributes #1, Typ SDK desky: vysokopevnostní+bílá; Object Layer Attributes #1, Způsob opláštění: Jednostranné; Object Layer Attributes #1, Tloušťka izolace (2): 0; Object Layer Attributes #1, Objemová hmotnost izolace: 0; Object Layer Attributes #1, Typ profilu pro SDK: CW 50; Object Layer Attributes #1, Rozteč rastru: 625
SDK ŠACHTOVÁ STĚNA/SDK OPL. S PO | Půdorys 1.PP | SDK ŠACHTOVÁ STĚNA/SDK OPL. S PO 0.075 m |  | SDK ŠACHTOVÁ STĚNA/SDK OPL. S PO |  | 1364HWa0000008256 | m3 | Celá stěna | Nový | Suché stavební práce | SDK ŠACHTOVÁ STĚNA/SDK OPL. S PO | no | 1364Stě0000008257 | m3 | Stěna |  | 0.075 | 3.54 | 3.322 | 0.266 | 1.2 | 0.249 | 0.09 | 2.95 | NEMSOK - Object Layer Attributes #1, Kód prvku: SN07.02.0001; Object Layer Attributes #1, Podlaží: 1.PP; Object Layer Attributes #1, Požární odolnost: bez požadavku; Object Layer Attributes #1, Funkce (venkovní): Ne; Object Layer Attributes #1, Statická funkce: Ne; Object Layer Attributes #1, Vlhkostní namáhání oboustranné: Ne; Object Layer Attributes #1, Tloušťka opláštění: 2×12,5; Object Layer Attributes #1, Typ SDK desky: vysokopevnostní+bílá; Object Layer Attributes #1, Způsob opláštění: Jednostranné; Object Layer Attributes #1, Tloušťka izolace (2): 0; Object Layer Attributes #1, Objemová hmotnost izolace: 0; Object Layer Attributes #1, Typ profilu pro SDK: CW 50; Object Layer Attributes #1, Rozteč rastru: 625
SDK ŠACHTOVÁ STĚNA/SDK OPL. S PO | Půdorys 1.PP | SDK ŠACHTOVÁ STĚNA/SDK OPL. S PO 0.075 m |  | SDK ŠACHTOVÁ STĚNA/SDK OPL. S PO |  | 1364HWa0000008267 | m3 | Celá stěna | Nový | Suché stavební práce | SDK ŠACHTOVÁ STĚNA/SDK OPL. S PO | no | 1364Stě0000008268 | m3 | Stěna |  | 0.075 | 0.516 | 0.516 | 0.039 | 0.175 | 0.039 | 0.013 | 2.95 | NEMSOK - Object Layer Attributes #1, Kód prvku: SN07.02.0001; Object Layer Attributes #1, Podlaží: 1.PP; Object Layer Attributes #1, Požární odolnost: bez požadavku; Object Layer Attributes #1, Funkce (venkovní): Ne; Object Layer Attributes #1, Statická funkce: Ne; Object Layer Attributes #1, Vlhkostní namáhání oboustranné: Ne; Object Layer Attributes #1, Tloušťka opláštění: 2×12,5; Object Layer Attributes #1, Typ SDK desky: vysokopevnostní+bílá; Object Layer Attributes #1, Způsob opláštění: Jednostranné; Object Layer Attributes #1, Tloušťka izolace (2): 0; Object Layer Attributes #1, Objemová hmotnost izolace: 0; Object Layer Attributes #1, Typ profilu pro SDK: CW 50; Object Layer Attributes #1, Rozteč rastru: 625
SDK - 1 KCE + DVOJITÉ OPLÁŠTĚNÍ | Půdorys 1.PP | SDK - 1 KCE + DVOJITÉ OPLÁŠTĚNÍ 0.125 m |  | SDK - 1 KCE + DVOJITÉ OPLÁŠTĚNÍ |  | 1364HWa0000008280 | m3 | Celá stěna | Nový | Suché stavební práce | SDK - 1 KCE + DVOJITÉ OPLÁŠTĚNÍ | no | 1364Stě0000008281 | m3 | Stěna |  | 0.125 | 13.344 | 10.655 | 1.668 | 4.375 | 1.296 | 0.547 | 3.05 | NEMSOK - Object Layer Attributes #1, Kód prvku: SN07.02.0001; Object Layer Attributes #1, Podlaží: 1.PP; Object Layer Attributes #1, Požární odolnost: EI 60; Object Layer Attributes #1, Funkce (venkovní): Ne; Object Layer Attributes #1, Statická funkce: Ne; Object Layer Attributes #1, Vážená stavební neprůzvučnost: 54; Object Layer Attributes #1, Vlhkostní namáhání oboustranné: Ne; Object Layer Attributes #1, Tloušťka opláštění: 2×12,5; Object Layer Attributes #1, Typ SDK desky: vysokopevnostní+bílá; Object Layer Attributes #1, Způsob opláštění: Oboustranné; Object Layer Attributes #1, Tloušťka izolace (2): 75; Object Layer Attributes #1, Objemová hmotnost izolace: 25; Object Layer Attributes #1, Typ profilu pro SDK: CW 75; Object Layer Attributes #1, Rozteč rastru: 625
SDK - 1 KCE + DVOJITÉ OPLÁŠTĚNÍ | Půdorys 1.PP | SDK - 1 KCE + DVOJITÉ OPLÁŠTĚNÍ 0.125 m |  | SDK - 1 KCE + DVOJITÉ OPLÁŠTĚNÍ |  | 1364HWa0000009845 | m3 | Celá stěna | Nový | Suché stavební práce | SDK - 1 KCE + DVOJITÉ OPLÁŠTĚNÍ | no | 1364Stě0000009846 | m3 | Stěna |  | 0.125 | 11.971 | 9.718 | 1.496 | 3.925 | 1.215 | 0.491 | 3.05 | NEMSOK - Object Layer Attributes #1, Kód prvku: SN07.02.0001; Object Layer Attributes #1, Podlaží: 1.PP; Object Layer Attributes #1, Požární odolnost: EI 60; Object Layer Attributes #1, Funkce (venkovní): Ne; Object Layer Attributes #1, Statická funkce: Ne; Object Layer Attributes #1, Vážená stavební neprůzvučnost: 54; Object Layer Attributes #1, Vlhkostní namáhání oboustranné: Ne; Object Layer Attributes #1, Tloušťka opláštění: 2×12,5; Object Layer Attributes #1, Typ SDK desky: vysokopevnostní+bílá; Object Layer Attributes #1, Způsob opláštění: Oboustranné; Object Layer Attributes #1, Tloušťka izolace (2): 75; Object Layer Attributes #1, Objemová hmotnost izolace: 25; Object Layer Attributes #1, Typ profilu pro SDK: CW 75; Object Layer Attributes #1, Rozteč rastru: 625
SDK - 1 KCE + DVOJITÉ OPLÁŠTĚNÍ | Půdorys 1.PP | SDK - 1 KCE + DVOJITÉ OPLÁŠTĚNÍ 0.125 m |  | SDK - 1 KCE + DVOJITÉ OPLÁŠTĚNÍ |  | 1364HWa0000010010 | m3 | Celá stěna | Nový | Suché stavební práce | SDK - 1 KCE + DVOJITÉ OPLÁŠTĚNÍ | no | 1364Stě0000010016 | m3 | Stěna |  | 0.125 | 8.083 | 8.083 | 1.01 | 2.65 | 1.01 | 0.331 | 3.05 | NEMSOK - Object Layer Attributes #1, Kód prvku: SN07.02.0001; Object Layer Attributes #1, Podlaží: 1.PP; Object Layer Attributes #1, Požární odolnost: EI 60; Object Layer Attributes #1, Funkce (venkovní): Ne; Object Layer Attributes #1, Statická funkce: Ne; Object Layer Attributes #1, Vážená stavební neprůzvučnost: 54; Object Layer Attributes #1, Vlhkostní namáhání oboustranné: Ne; Object Layer Attributes #1, Tloušťka opláštění: 2×12,5; Object Layer Attributes #1, Typ SDK desky: vysokopevnostní+bílá; Object Layer Attributes #1, Způsob opláštění: Oboustranné; Object Layer Attributes #1, Tloušťka izolace (2): 75; Object Layer Attributes #1, Objemová hmotnost izolace: 25; Object Layer Attributes #1, Typ profilu pro SDK: CW 75; Object Layer Attributes #1, Rozteč rastru: 625
SDK - 1 KCE + DVOJITÉ OPLÁŠTĚNÍ | Půdorys 1.PP | SDK - 1 KCE + DVOJITÉ OPLÁŠTĚNÍ 0.1 m |  | SDK - 1 KCE + DVOJITÉ OPLÁŠTĚNÍ |  | 1364HWa0000010014 | m3 | Celá stěna | Nový | Suché stavební práce | SDK - 1 KCE + DVOJITÉ OPLÁŠTĚNÍ | no | 1364Stě0000010046 | m3 | Stěna |  | 0.1 | 4.27 | 2.539 | 0.427 | 1.4 | 0.254 | 0.14 | 3.05 | NEMSOK - Object Layer Attributes #1, Kód prvku: SN07.02.0001; Object Layer Attributes #1, Podlaží: 1.PP; Object Layer Attributes #1, Požární odolnost: EI 60; Object Layer Attributes #1, Funkce (venkovní): Ne; Object Layer Attributes #1, Statická funkce: Ne; Object Layer Attributes #1, Vážená stavební neprůzvučnost: 54; Object Layer Attributes #1, Vlhkostní namáhání oboustranné: Ne; Object Layer Attributes #1, Tloušťka opláštění: 2×12,5; Object Layer Attributes #1, Typ SDK desky: vysokopevnostní+bílá; Object Layer Attributes #1, Způsob opláštění: Oboustranné; Object Layer Attributes #1, Tloušťka izolace (2): 50; Object Layer Attributes #1, Objemová hmotnost izolace: 25; Object Layer Attributes #1, Typ profilu pro SDK: CW 50; Object Layer Attributes #1, Rozteč rastru: 625
SDK - 1 KCE + DVOJITÉ OPLÁŠTĚNÍ | Půdorys 1.PP | SDK - 1 KCE + DVOJITÉ OPLÁŠTĚNÍ 0.15 m |  | SDK - 1 KCE + DVOJITÉ OPLÁŠTĚNÍ |  | 1364HWa0000010271 | m3 | Celá stěna | Nový | Suché stavební práce | SDK - 1 KCE + DVOJITÉ OPLÁŠTĚNÍ | no | 1364Stě0000010290 | m3 | Stěna |  | 0.15 | 2.898 | 2.898 | 0.435 | 0.95 | 0.435 | 0.143 | 3.05 | NEMSOK - Object Layer Attributes #1, Kód prvku: SN07.02.0001; Object Layer Attributes #1, Podlaží: 1.PP; Object Layer Attributes #1, Požární odolnost: EI 60; Object Layer Attributes #1, Funkce (venkovní): Ne; Object Layer Attributes #1, Statická funkce: Ne; Object Layer Attributes #1, Vážená stavební neprůzvučnost: 54; Object Layer Attributes #1, Vlhkostní namáhání oboustranné: Ne; Object Layer Attributes #1, Tloušťka opláštění: 2×12,5; Object Layer Attributes #1, Typ SDK desky: vysokopevnostní+bílá; Object Layer Attributes #1, Způsob opláštění: Oboustranné; Object Layer Attributes #1, Tloušťka izolace (2): 100; Object Layer Attributes #1, Objemová hmotnost izolace: 25; Object Layer Attributes #1, Typ profilu pro SDK: CW 100; Object Layer Attributes #1, Rozteč rastru: 625
SDK - 2 KCE + DVOJITÉ OPLÁŠTĚNÍ | Půdorys 1.PP | SDK - 2 KCE + DVOJITÉ OPLÁŠTĚNÍ 0.25 m |  | SDK - 2 KCE + DVOJITÉ OPLÁŠTĚNÍ |  | 1364HWa0000010309 | m3 | Celá stěna | Nový | Suché stavební práce | SDK - 2 KCE + DVOJITÉ OPLÁŠTĚNÍ | no | 1364Stě0000010327 | m3 | Stěna |  | 0.25 | 4.27 | 4.27 | 1.067 | 1.4 | 1.065 | 0.35 | 3.05 | NEMSOK - Object Layer Attributes #1, Kód prvku: SN07.02.0001; Object Layer Attributes #1, Podlaží: 1.PP; Object Layer Attributes #1, Požární odolnost: EI 60; Object Layer Attributes #1, Funkce (venkovní): Ne; Object Layer Attributes #1, Statická funkce: Ne; Object Layer Attributes #1, Vážená stavební neprůzvučnost: 54; Object Layer Attributes #1, Vlhkostní namáhání oboustranné: Ne; Object Layer Attributes #1, Tloušťka opláštění: 2×12,5; Object Layer Attributes #1, Typ SDK desky: vysokopevnostní+bílá; Object Layer Attributes #1, Způsob opláštění: Oboustranné; Object Layer Attributes #1, Tloušťka izolace (2): 100; Object Layer Attributes #1, Objemová hmotnost izolace: 25; Object Layer Attributes #1, Typ profilu pro SDK: 2× CW 100; Object Layer Attributes #1, Rozteč rastru: 625
SDK - 1 KCE + DVOJITÉ OPLÁŠTĚNÍ | Půdorys 1.PP | SDK - 1 KCE + DVOJITÉ OPLÁŠTĚNÍ 0.15 m |  | SDK - 1 KCE + DVOJITÉ OPLÁŠTĚNÍ |  | 1364HWa0000010574 | m3 | Celá stěna | Nový | Suché stavební práce | SDK - 1 KCE + DVOJITÉ OPLÁŠTĚNÍ | no | 1364Stě0000010820 | m3 | Stěna |  | 0.15 | 10.955 | 6.913 | 1.643 | 3.592 | 1.079 | 0.539 | 3.05 | NEMSOK - Object Layer Attributes #1, Kód prvku: SN07.02.0001; Object Layer Attributes #1, Podlaží: 1.PP; Object Layer Attributes #1, Požární odolnost: EI 60; Object Layer Attributes #1, Funkce (venkovní): Ne; Object Layer Attributes #1, Statická funkce: Ne; Object Layer Attributes #1, Vážená stavební neprůzvučnost: 54; Object Layer Attributes #1, Vlhkostní namáhání oboustranné: Ne; Object Layer Attributes #1, Tloušťka opláštění: 2×12,5; Object Layer Attributes #1, Typ SDK desky: vysokopevnostní+bílá; Object Layer Attributes #1, Způsob opláštění: Oboustranné; Object Layer Attributes #1, Tloušťka izolace (2): 100; Object Layer Attributes #1, Objemová hmotnost izolace: 25; Object Layer Attributes #1, Typ profilu pro SDK: CW 100; Object Layer Attributes #1, Rozteč rastru: 625
SDK - 1 KCE + DVOJITÉ OPLÁŠTĚNÍ | Půdorys 1.PP | SDK - 1 KCE + DVOJITÉ OPLÁŠTĚNÍ 0.1 m |  | SDK - 1 KCE + DVOJITÉ OPLÁŠTĚNÍ |  | 1364HWa0000010583 | m3 | Celá stěna | Nový | Suché stavební práce | SDK - 1 KCE + DVOJITÉ OPLÁŠTĚNÍ | no | 1364Stě0000010810 | m3 | Stěna |  | 0.1 | 8.387 | 8.218 | 0.839 | 2.75 | 0.822 | 0.275 | 3.05 | NEMSOK - Object Layer Attributes #1, Kód prvku: SN07.02.0001; Object Layer Attributes #1, Podlaží: 1.PP; Object Layer Attributes #1, Požární odolnost: EI 60; Object Layer Attributes #1, Funkce (venkovní): Ne; Object Layer Attributes #1, Statická funkce: Ne; Object Layer Attributes #1, Vážená stavební neprůzvučnost: 54; Object Layer Attributes #1, Vlhkostní namáhání oboustranné: Ne; Object Layer Attributes #1, Tloušťka opláštění: 2×12,5; Object Layer Attributes #1, Typ SDK desky: vysokopevnostní+bílá; Object Layer Attributes #1, Způsob opláštění: Oboustranné; Object Layer Attributes #1, Tloušťka izolace (2): 50; Object Layer Attributes #1, Objemová hmotnost izolace: 25; Object Layer Attributes #1, Typ profilu pro SDK: CW 50; Object Layer Attributes #1, Rozteč rastru: 625
SDK - 2 KCE + DVOJITÉ OPLÁŠTĚNÍ | Půdorys 1.PP | SDK - 2 KCE + DVOJITÉ OPLÁŠTĚNÍ 0.25 m |  | SDK - 2 KCE + DVOJITÉ OPLÁŠTĚNÍ |  | 1364HWa0000010598 | m3 | Celá stěna | Nový | Suché stavební práce | SDK - 2 KCE + DVOJITÉ OPLÁŠTĚNÍ | no | 1364Stě0000010638 | m3 | Stěna |  | 0.25 | 2.655 | 2.655 | 0.664 | 0.9 | 0.662 | 0.225 | 2.95 | NEMSOK - Object Layer Attributes #1, Kód prvku: SN07.02.0001; Object Layer Attributes #1, Podlaží: 1.PP; Object Layer Attributes #1, Požární odolnost: EI 60; Object Layer Attributes #1, Funkce (venkovní): Ne; Object Layer Attributes #1, Statická funkce: Ne; Object Layer Attributes #1, Vážená stavební neprůzvučnost: 54; Object Layer Attributes #1, Vlhkostní namáhání oboustranné: Ne; Object Layer Attributes #1, Tloušťka opláštění: 2×12,5; Object Layer Attributes #1, Typ SDK desky: vysokopevnostní+bílá; Object Layer Attributes #1, Způsob opláštění: Oboustranné; Object Layer Attributes #1, Tloušťka izolace (2): 100; Object Layer Attributes #1, Objemová hmotnost izolace: 25; Object Layer Attributes #1, Typ profilu pro SDK: 2× CW 100; Object Layer Attributes #1, Rozteč rastru: 625
SDK - 1 KCE + DVOJITÉ OPLÁŠTĚNÍ | Půdorys 1.PP | SDK - 1 KCE + DVOJITÉ OPLÁŠTĚNÍ 0.1 m |  | SDK - 1 KCE + DVOJITÉ OPLÁŠTĚNÍ |  | 1364HWa0000010599 | m3 | Celá stěna | Nový | Suché stavební práce | SDK - 1 KCE + DVOJITÉ OPLÁŠTĚNÍ | no | 1364Stě0000010652 | m3 | Stěna |  | 0.1 | 5.337 | 5.158 | 0.534 | 1.75 | 0.516 | 0.175 | 3.05 | NEMSOK - Object Layer Attributes #1, Kód prvku: SN07.02.0001; Object Layer Attributes #1, Podlaží: 1.PP; Object Layer Attributes #1, Požární odolnost: EI 60; Object Layer Attributes #1, Funkce (venkovní): Ne; Object Layer Attributes #1, Statická funkce: Ne; Object Layer Attributes #1, Vážená stavební neprůzvučnost: 54; Object Layer Attributes #1, Vlhkostní namáhání oboustranné: Ne; Object Layer Attributes #1, Tloušťka opláštění: 2×12,5; Object Layer Attributes #1, Typ SDK desky: vysokopevnostní+bílá; Object Layer Attributes #1, Způsob opláštění: Oboustranné; Object Layer Attributes #1, Tloušťka izolace (2): 50; Object Layer Attributes #1, Objemová hmotnost izolace: 25; Object Layer Attributes #1, Typ profilu pro SDK: CW 50; Object Layer Attributes #1, Rozteč rastru: 625
SDK INSTAL. PŘDSTĚNA VYSOKÁ | Půdorys 1.PP | SDK INSTAL. PŘDSTĚNA VYSOKÁ 0.15 m |  | SDK INSTAL. PŘDSTĚNA VYSOKÁ |  | 1364HWa0000010606 | m3 | Celá stěna | Nový | Suché stavební práce | SDK INSTAL. PŘDSTĚNA VYSOKÁ | no | 1364Stě0000010826 | m3 | Stěna |  | 0.15 | 4.72 | 4.72 | 0.708 | 1.6 | 0.708 | 0.24 | 2.95 | NEMSOK - Object Layer Attributes #1, Kód prvku: SN07.02.0001; Object Layer Attributes #1, Podlaží: 1.PP; Object Layer Attributes #1, Požární odolnost: bez požadavku; Object Layer Attributes #1, Funkce (venkovní): Ne; Object Layer Attributes #1, Statická funkce: Ne; Object Layer Attributes #1, Vlhkostní namáhání oboustranné: Ne; Object Layer Attributes #1, Tloušťka opláštění: 2×12,5; Object Layer Attributes #1, Typ SDK desky: impregnovaná; Object Layer Attributes #1, Způsob opláštění: Jednostranné; Object Layer Attributes #1, Tloušťka izolace (2): 0; Object Layer Attributes #1, Objemová hmotnost izolace: 0; Object Layer Attributes #1, Typ profilu pro SDK: CW 50; Object Layer Attributes #1, Rozteč rastru: 625
SDK - 1 KCE + DVOJITÉ OPLÁŠTĚNÍ | Půdorys 1.PP | SDK - 1 KCE + DVOJITÉ OPLÁŠTĚNÍ 0.1 m |  | SDK - 1 KCE + DVOJITÉ OPLÁŠTĚNÍ |  | 1364HWa0000010609 | m3 | Celá stěna | Nový | Suché stavební práce | SDK - 1 KCE + DVOJITÉ OPLÁŠTĚNÍ | no | 1364Stě0000010814 | m3 | Stěna |  | 0.1 | 3.507 | 1.778 | 0.351 | 1.15 | 0.178 | 0.115 | 3.05 | NEMSOK - Object Layer Attributes #1, Kód prvku: SN07.02.0001; Object Layer Attributes #1, Podlaží: 1.PP; Object Layer Attributes #1, Požární odolnost: EI 60; Object Layer Attributes #1, Funkce (venkovní): Ne; Object Layer Attributes #1, Statická funkce: Ne; Object Layer Attributes #1, Vážená stavební neprůzvučnost: 54; Object Layer Attributes #1, Vlhkostní namáhání oboustranné: Ne; Object Layer Attributes #1, Tloušťka opláštění: 2×12,5; Object Layer Attributes #1, Typ SDK desky: vysokopevnostní+bílá; Object Layer Attributes #1, Způsob opláštění: Oboustranné; Object Layer Attributes #1, Tloušťka izolace (2): 50; Object Layer Attributes #1, Objemová hmotnost izolace: 25; Object Layer Attributes #1, Typ profilu pro SDK: CW 50; Object Layer Attributes #1, Rozteč rastru: 625
SDK ŠACHTOVÁ STĚNA/SDK OPL. S PO | Půdorys 1.PP | SDK ŠACHTOVÁ STĚNA/SDK OPL. S PO 0.075 m |  | SDK ŠACHTOVÁ STĚNA/SDK OPL. S PO |  | 1364HWa0000010630 | m3 | Celá stěna | Nový | Suché stavební práce | SDK ŠACHTOVÁ STĚNA/SDK OPL. S PO | no | 1364Stě0000010654 | m3 | Stěna |  | 0.075 | 2.581 | 2.365 | 0.194 | 0.875 | 0.177 | 0.066 | 2.95 | NEMSOK - Object Layer Attributes #1, Kód prvku: SN07.02.0001; Object Layer Attributes #1, Podlaží: 1.PP; Object Layer Attributes #1, Požární odolnost: bez požadavku; Object Layer Attributes #1, Funkce (venkovní): Ne; Object Layer Attributes #1, Statická funkce: Ne; Object Layer Attributes #1, Vlhkostní namáhání oboustranné: Ne; Object Layer Attributes #1, Tloušťka opláštění: 2×12,5; Object Layer Attributes #1, Typ SDK desky: vysokopevnostní+bílá; Object Layer Attributes #1, Způsob opláštění: Jednostranné; Object Layer Attributes #1, Tloušťka izolace (2): 0; Object Layer Attributes #1, Objemová hmotnost izolace: 0; Object Layer Attributes #1, Typ profilu pro SDK: CW 50; Object Layer Attributes #1, Rozteč rastru: 625
SDK - 1 KCE + DVOJITÉ OPLÁŠTĚNÍ | Půdorys 1.PP | SDK - 1 KCE + DVOJITÉ OPLÁŠTĚNÍ 0.15 m |  | SDK - 1 KCE + DVOJITÉ OPLÁŠTĚNÍ |  | 1364HWa0000010640 | m3 | Celá stěna | Nový | Suché stavební práce | SDK - 1 KCE + DVOJITÉ OPLÁŠTĚNÍ | no | 1364Stě0000010648 | m3 | Stěna |  | 0.15 | 4.194 | 4.194 | 0.629 | 1.375 | 0.629 | 0.206 | 3.05 | NEMSOK - Object Layer Attributes #1, Kód prvku: SN07.02.0001; Object Layer Attributes #1, Podlaží: 1.PP; Object Layer Attributes #1, Požární odolnost: EI 60; Object Layer Attributes #1, Funkce (venkovní): Ne; Object Layer Attributes #1, Statická funkce: Ne; Object Layer Attributes #1, Vážená stavební neprůzvučnost: 54; Object Layer Attributes #1, Vlhkostní namáhání oboustranné: Ne; Object Layer Attributes #1, Tloušťka opláštění: 2×12,5; Object Layer Attributes #1, Typ SDK desky: vysokopevnostní+bílá; Object Layer Attributes #1, Způsob opláštění: Oboustranné; Object Layer Attributes #1, Tloušťka izolace (2): 100; Object Layer Attributes #1, Objemová hmotnost izolace: 25; Object Layer Attributes #1, Typ profilu pro SDK: CW 100; Object Layer Attributes #1, Rozteč rastru: 625
SDK - 1 KCE + DVOJITÉ OPLÁŠTĚNÍ | Půdorys 1.PP | SDK - 1 KCE + DVOJITÉ OPLÁŠTĚNÍ 0.125 m |  | SDK - 1 KCE + DVOJITÉ OPLÁŠTĚNÍ |  | 1364HWa0000010642 | m3 | Celá stěna | Nový | Suché stavební práce | SDK - 1 KCE + DVOJITÉ OPLÁŠTĚNÍ | no | 1364Stě0000010668 | m3 | Stěna |  | 0.125 | 8.082 | 8.083 | 1.01 | 2.65 | 1.01 | 0.331 | 3.05 | NEMSOK - Object Layer Attributes #1, Kód prvku: SN07.02.0001; Object Layer Attributes #1, Podlaží: 1.PP; Object Layer Attributes #1, Požární odolnost: EI 60; Object Layer Attributes #1, Funkce (venkovní): Ne; Object Layer Attributes #1, Statická funkce: Ne; Object Layer Attributes #1, Vážená stavební neprůzvučnost: 54; Object Layer Attributes #1, Vlhkostní namáhání oboustranné: Ne; Object Layer Attributes #1, Tloušťka opláštění: 2×12,5; Object Layer Attributes #1, Typ SDK desky: vysokopevnostní+bílá; Object Layer Attributes #1, Způsob opláštění: Oboustranné; Object Layer Attributes #1, Tloušťka izolace (2): 75; Object Layer Attributes #1, Objemová hmotnost izolace: 25; Object Layer Attributes #1, Typ profilu pro SDK: CW 75; Object Layer Attributes #1, Rozteč rastru: 625
SDK - 1 KCE + DVOJITÉ OPLÁŠTĚNÍ | Půdorys 1.PP | SDK - 1 KCE + DVOJITÉ OPLÁŠTĚNÍ 0.125 m |  | SDK - 1 KCE + DVOJITÉ OPLÁŠTĚNÍ |  | 1364HWa0000010643 | m3 | Celá stěna | Nový | Suché stavební práce | SDK - 1 KCE + DVOJITÉ OPLÁŠTĚNÍ | no | 1364Stě0000010650 | m3 | Stěna |  | 0.125 | 1.067 | 1.068 | 0.133 | 0.35 | 0.133 | 0.044 | 3.05 | NEMSOK - Object Layer Attributes #1, Kód prvku: SN07.02.0001; Object Layer Attributes #1, Podlaží: 1.PP; Object Layer Attributes #1, Požární odolnost: EI 60; Object Layer Attributes #1, Funkce (venkovní): Ne; Object Layer Attributes #1, Statická funkce: Ne; Object Layer Attributes #1, Vážená stavební neprůzvučnost: 54; Object Layer Attributes #1, Vlhkostní namáhání oboustranné: Ne; Object Layer Attributes #1, Tloušťka opláštění: 2×12,5; Object Layer Attributes #1, Typ SDK desky: vysokopevnostní+bílá; Object Layer Attributes #1, Způsob opláštění: Oboustranné; Object Layer Attributes #1, Tloušťka izolace (2): 75; Object Layer Attributes #1, Objemová hmotnost izolace: 25; Object Layer Attributes #1, Typ profilu pro SDK: CW 75; Object Layer Attributes #1, Rozteč rastru: 625
SDK - 1 KCE + DVOJITÉ OPLÁŠTĚNÍ | Půdorys 1.PP | SDK - 1 KCE + DVOJITÉ OPLÁŠTĚNÍ 0.15 m |  | SDK - 1 KCE + DVOJITÉ OPLÁŠTĚNÍ |  | 1364HWa0000010705 | m3 | Celá stěna | Nový | Suché stavební práce | SDK - 1 KCE + DVOJITÉ OPLÁŠTĚNÍ | no | 1364Stě0000010790 | m3 | Stěna |  | 0.15 | 7.625 | 7.576 | 1.144 | 2.5 | 1.136 | 0.375 | 3.05 | NEMSOK - Object Layer Attributes #1, Kód prvku: SN07.02.0001; Object Layer Attributes #1, Podlaží: 1.PP; Object Layer Attributes #1, Požární odolnost: EI 60; Object Layer Attributes #1, Funkce (venkovní): Ne; Object Layer Attributes #1, Statická funkce: Ne; Object Layer Attributes #1, Vážená stavební neprůzvučnost: 54; Object Layer Attributes #1, Vlhkostní namáhání oboustranné: Ne; Object Layer Attributes #1, Tloušťka opláštění: 2×12,5; Object Layer Attributes #1, Typ SDK desky: vysokopevnostní+bílá; Object Layer Attributes #1, Způsob opláštění: Oboustranné; Object Layer Attributes #1, Tloušťka izolace (2): 100; Object Layer Attributes #1, Objemová hmotnost izolace: 25; Object Layer Attributes #1, Typ profilu pro SDK: CW 100; Object Layer Attributes #1, Rozteč rastru: 625
SDK - 1 KCE + DVOJITÉ OPLÁŠTĚNÍ | Půdorys 1.PP | SDK - 1 KCE + DVOJITÉ OPLÁŠTĚNÍ 0.1 m |  | SDK - 1 KCE + DVOJITÉ OPLÁŠTĚNÍ |  | 1364HWa0000010706 | m3 | Celá stěna | Nový | Suché stavební práce | SDK - 1 KCE + DVOJITÉ OPLÁŠTĚNÍ | no | 1364Stě0000010785 | m3 | Stěna |  | 0.1 | 4.422 | 2.692 | 0.442 | 1.45 | 0.269 | 0.145 | 3.05 | NEMSOK - Object Layer Attributes #1, Kód prvku: SN07.02.0001; Object Layer Attributes #1, Podlaží: 1.PP; Object Layer Attributes #1, Požární odolnost: EI 60; Object Layer Attributes #1, Funkce (venkovní): Ne; Object Layer Attributes #1, Statická funkce: Ne; Object Layer Attributes #1, Vážená stavební neprůzvučnost: 54; Object Layer Attributes #1, Vlhkostní namáhání oboustranné: Ne; Object Layer Attributes #1, Tloušťka opláštění: 2×12,5; Object Layer Attributes #1, Typ SDK desky: vysokopevnostní+bílá; Object Layer Attributes #1, Způsob opláštění: Oboustranné; Object Layer Attributes #1, Tloušťka izolace (2): 50; Object Layer Attributes #1, Objemová hmotnost izolace: 25; Object Layer Attributes #1, Typ profilu pro SDK: CW 50; Object Layer Attributes #1, Rozteč rastru: 625; Object Layer Attributes #1, Způsob položení: flexibilní tmel; Object Layer Attributes #1, Typ hydroizolace: bez
SDK - 1 KCE + DVOJITÉ OPLÁŠTĚNÍ | Půdorys 1.PP | SDK - 1 KCE + DVOJITÉ OPLÁŠTĚNÍ 0.1 m |  | SDK - 1 KCE + DVOJITÉ OPLÁŠTĚNÍ |  | 1364HWa0000010707 | m3 | Celá stěna | Nový | Suché stavební práce | SDK - 1 KCE + DVOJITÉ OPLÁŠTĚNÍ | no | 1364Stě0000010788 | m3 | Stěna |  | 0.1 | 5.49 | 3.711 | 0.549 | 1.8 | 0.371 | 0.18 | 3.05 | NEMSOK - Object Layer Attributes #1, Kód prvku: SN07.02.0001; Object Layer Attributes #1, Podlaží: 1.PP; Object Layer Attributes #1, Požární odolnost: EI 60; Object Layer Attributes #1, Funkce (venkovní): Ne; Object Layer Attributes #1, Statická funkce: Ne; Object Layer Attributes #1, Vážená stavební neprůzvučnost: 54; Object Layer Attributes #1, Vlhkostní namáhání oboustranné: Ne; Object Layer Attributes #1, Tloušťka opláštění: 2×12,5; Object Layer Attributes #1, Typ SDK desky: vysokopevnostní+bílá; Object Layer Attributes #1, Způsob opláštění: Oboustranné; Object Layer Attributes #1, Tloušťka izolace (2): 50; Object Layer Attributes #1, Objemová hmotnost izolace: 25; Object Layer Attributes #1, Typ profilu pro SDK: CW 50; Object Layer Attributes #1, Rozteč rastru: 625
SDK - 2 KCE + DVOJITÉ OPLÁŠTĚNÍ | Půdorys 1.PP | SDK - 2 KCE + DVOJITÉ OPLÁŠTĚNÍ 0.25 m |  | SDK - 2 KCE + DVOJITÉ OPLÁŠTĚNÍ |  | 1364HWa0000010772 | m3 | Celá stěna | Nový | Suché stavební práce | SDK - 2 KCE + DVOJITÉ OPLÁŠTĚNÍ | no | 1364Stě0000010797 | m3 | Stěna |  | 0.25 | 2.655 | 2.655 | 0.664 | 0.9 | 0.664 | 0.225 | 2.95 | NEMSOK - Object Layer Attributes #1, Kód prvku: SN07.02.0001; Object Layer Attributes #1, Podlaží: 1.PP; Object Layer Attributes #1, Požární odolnost: EI 60; Object Layer Attributes #1, Funkce (venkovní): Ne; Object Layer Attributes #1, Statická funkce: Ne; Object Layer Attributes #1, Vážená stavební neprůzvučnost: 54; Object Layer Attributes #1, Vlhkostní namáhání oboustranné: Ne; Object Layer Attributes #1, Tloušťka opláštění: 2×12,5; Object Layer Attributes #1, Typ SDK desky: vysokopevnostní+bílá; Object Layer Attributes #1, Způsob opláštění: Oboustranné; Object Layer Attributes #1, Tloušťka izolace (2): 100; Object Layer Attributes #1, Objemová hmotnost izolace: 25; Object Layer Attributes #1, Typ profilu pro SDK: 2× CW 100; Object Layer Attributes #1, Rozteč rastru: 625
SDK - 2 KCE + DVOJITÉ OPLÁŠTĚNÍ | Půdorys 1.PP | SDK - 2 KCE + DVOJITÉ OPLÁŠTĚNÍ 0.25 m |  | SDK - 2 KCE + DVOJITÉ OPLÁŠTĚNÍ |  | 1364HWa0000010805 | m3 | Celá stěna | Nový | Suché stavební práce | SDK - 2 KCE + DVOJITÉ OPLÁŠTĚNÍ | no | 1364Stě0000010838 | m3 | Stěna |  | 0.25 | 3.983 | 3.936 | 0.996 | 1.35 | 0.979 | 0.337 | 2.95 | NEMSOK - Object Layer Attributes #1, Kód prvku: SN07.02.0001; Object Layer Attributes #1, Podlaží: 1.PP; Object Layer Attributes #1, Požární odolnost: EI 60; Object Layer Attributes #1, Funkce (venkovní): Ne; Object Layer Attributes #1, Statická funkce: Ne; Object Layer Attributes #1, Vážená stavební neprůzvučnost: 54; Object Layer Attributes #1, Vlhkostní namáhání oboustranné: Ne; Object Layer Attributes #1, Tloušťka opláštění: 2×12,5; Object Layer Attributes #1, Typ SDK desky: vysokopevnostní+bílá; Object Layer Attributes #1, Způsob opláštění: Oboustranné; Object Layer Attributes #1, Tloušťka izolace (2): 100; Object Layer Attributes #1, Objemová hmotnost izolace: 25; Object Layer Attributes #1, Typ profilu pro SDK: 2× CW 100; Object Layer Attributes #1, Rozteč rastru: 625
SDK - 1 KCE + DVOJITÉ OPLÁŠTĚNÍ | Půdorys 1.PP | SDK - 1 KCE + DVOJITÉ OPLÁŠTĚNÍ 0.1 m |  | SDK - 1 KCE + DVOJITÉ OPLÁŠTĚNÍ |  | 1364HWa0000010807 | m3 | Celá stěna | Nový | Suché stavební práce | SDK - 1 KCE + DVOJITÉ OPLÁŠTĚNÍ | no | 1364Stě0000010828 | m3 | Stěna |  | 0.1 | 2.47 | 2.383 | 0.247 | 0.81 | 0.238 | 0.081 | 3.05 | NEMSOK - Object Layer Attributes #1, Kód prvku: SN07.02.0001; Object Layer Attributes #1, Podlaží: 1.PP; Object Layer Attributes #1, Požární odolnost: EI 60; Object Layer Attributes #1, Funkce (venkovní): Ne; Object Layer Attributes #1, Statická funkce: Ne; Object Layer Attributes #1, Vážená stavební neprůzvučnost: 54; Object Layer Attributes #1, Vlhkostní namáhání oboustranné: Ne; Object Layer Attributes #1, Tloušťka opláštění: 2×12,5; Object Layer Attributes #1, Typ SDK desky: vysokopevnostní+bílá; Object Layer Attributes #1, Způsob opláštění: Oboustranné; Object Layer Attributes #1, Tloušťka izolace (2): 50; Object Layer Attributes #1, Objemová hmotnost izolace: 25; Object Layer Attributes #1, Typ profilu pro SDK: CW 50; Object Layer Attributes #1, Rozteč rastru: 625
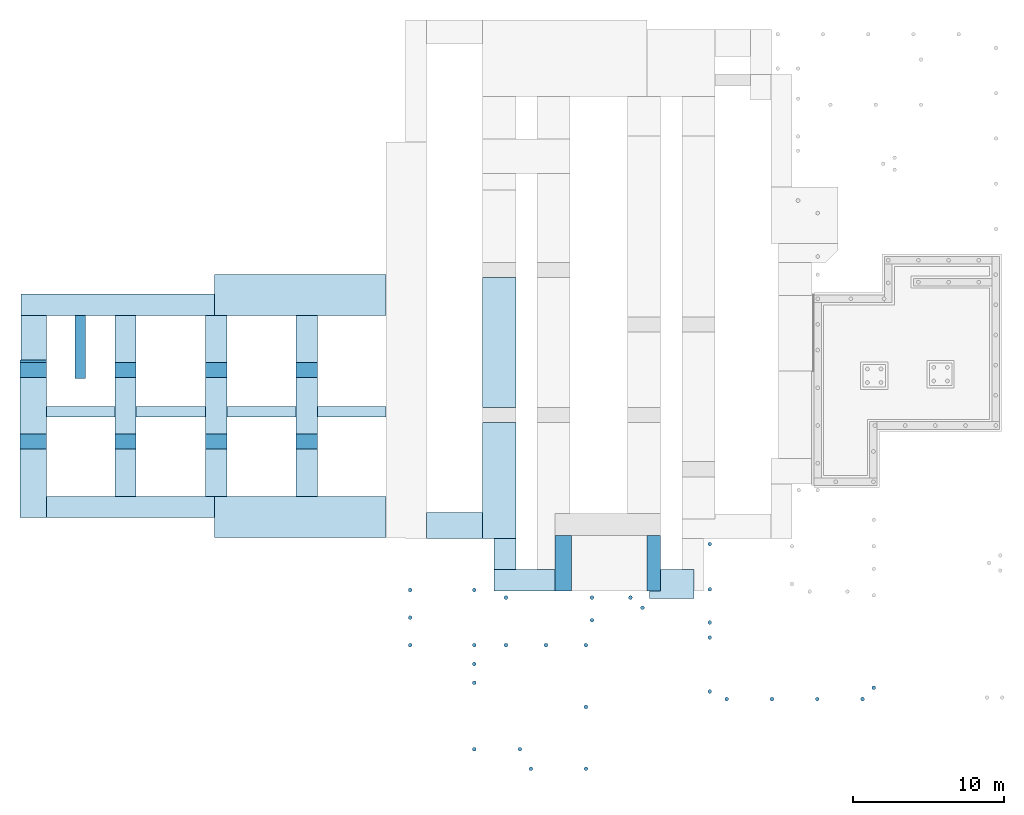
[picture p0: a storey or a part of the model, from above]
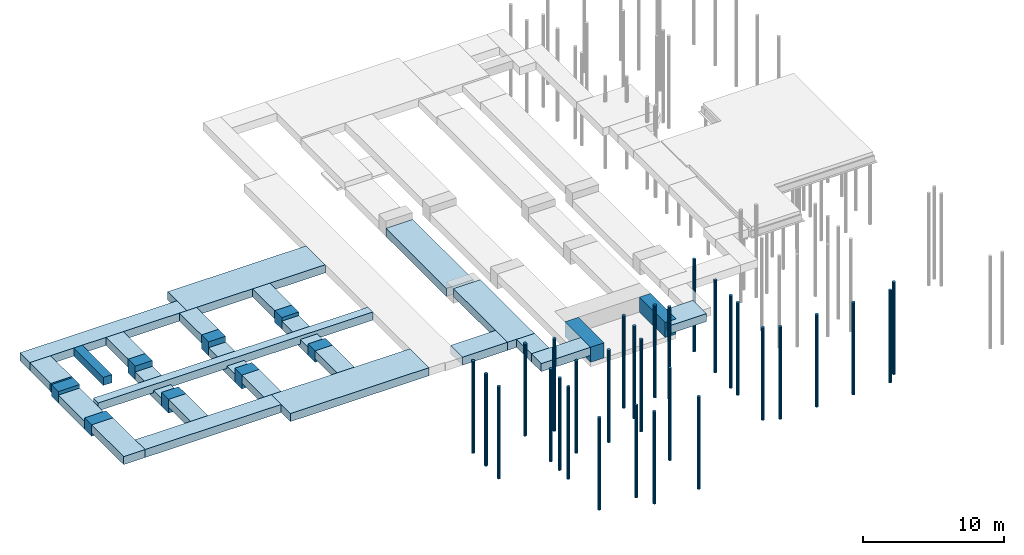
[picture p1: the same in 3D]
Properties of the parts of a building model (IFC4), part 30 of 45

# IfcWall (2385)
Name | In | Material | Faktor | Označení | Požární odolnost | Allright_Stavebni_dil_ID | Jednotka | Název_objektu | Object Layer Attributes #1, Status | Object Layer Attributes #1, Práce | Object Layer Attributes #1, Materiál | Object Layer Attributes #1, Staticky nosná konstrukce | Object Layer Attributes #1, Allright_Stavebni_dil_ID | Object Layer Attributes #1, Jednotka | Object Layer Attributes #1, Název_objektu | ThermalTransmittance (W/K/m2) | Width (m) | GrossSideArea (m2) | NetSideArea (m2) | GrossVolume (m3) | Length (m) | NetVolume (m3) | GrossFootprintArea (m2) | Height (m)
SDK - 1 KCE + DVOJITÉ OPLÁŠTĚNÍ | Půdorys 1.PP | SDK - 1 KCE + DVOJITÉ OPLÁŠTĚNÍ 0.15 m |  | SDK - 1 KCE + DVOJITÉ OPLÁŠTĚNÍ |  | 1364HWa0000010823 | m3 | Celá stěna | Nový | Suché stavební práce | SDK - 1 KCE + DVOJITÉ OPLÁŠTĚNÍ | no | 1364Stě0000010834 | m3 | Stěna |  | 0.15 | 0.152 | 0.153 | 0.023 | 0.05 | 0.023 | 0.007 | 3.05 | NEMSOK - Object Layer Attributes #1, Kód prvku: SN07.02.0001; Object Layer Attributes #1, Podlaží: 1.PP; Object Layer Attributes #1, Požární odolnost: EI 60; Object Layer Attributes #1, Funkce (venkovní): Ne; Object Layer Attributes #1, Statická funkce: Ne; Object Layer Attributes #1, Vážená stavební neprůzvučnost: 54; Object Layer Attributes #1, Vlhkostní namáhání oboustranné: Ne; Object Layer Attributes #1, Tloušťka opláštění: 2×12,5; Object Layer Attributes #1, Typ SDK desky: vysokopevnostní+bílá; Object Layer Attributes #1, Způsob opláštění: Oboustranné; Object Layer Attributes #1, Tloušťka izolace (2): 100; Object Layer Attributes #1, Objemová hmotnost izolace: 25; Object Layer Attributes #1, Typ profilu pro SDK: CW 100; Object Layer Attributes #1, Rozteč rastru: 625
SDK - 1 KCE + DVOJITÉ OPLÁŠTĚNÍ | Půdorys 1.PP | SDK - 1 KCE + DVOJITÉ OPLÁŠTĚNÍ 0.125 m |  | SDK - 1 KCE + DVOJITÉ OPLÁŠTĚNÍ |  | 1364HWa0000011076 | m3 | Celá stěna | Nový | Suché stavební práce | SDK - 1 KCE + DVOJITÉ OPLÁŠTĚNÍ | no | 1364Stě0000011129 | m3 | Stěna |  | 0.125 | 16.714 | 8.967 | 2.089 | 5.48 | 1.159 | 0.685 | 3.05 | NEMSOK - Object Layer Attributes #1, Kód prvku: SN07.02.0001; Object Layer Attributes #1, Podlaží: 1.PP; Object Layer Attributes #1, Požární odolnost: EI 60; Object Layer Attributes #1, Funkce (venkovní): Ne; Object Layer Attributes #1, Statická funkce: Ne; Object Layer Attributes #1, Vážená stavební neprůzvučnost: 54; Object Layer Attributes #1, Vlhkostní namáhání oboustranné: Ne; Object Layer Attributes #1, Tloušťka opláštění: 2×12,5; Object Layer Attributes #1, Typ SDK desky: vysokopevnostní+bílá; Object Layer Attributes #1, Způsob opláštění: Oboustranné; Object Layer Attributes #1, Tloušťka izolace (2): 75; Object Layer Attributes #1, Objemová hmotnost izolace: 25; Object Layer Attributes #1, Typ profilu pro SDK: CW 75; Object Layer Attributes #1, Rozteč rastru: 625
SDK ŠACHTOVÁ STĚNA/SDK OPL. S PO | Půdorys 1.PP | SDK ŠACHTOVÁ STĚNA/SDK OPL. S PO 0.075 m |  | SDK ŠACHTOVÁ STĚNA/SDK OPL. S PO |  | 1364HWa0798472895 | m3 | Celá stěna | Nový | Suché stavební práce | SDK ŠACHTOVÁ STĚNA/SDK OPL. S PO | no | 1364Stě0798472896 | m3 | Stěna |  | 0.075 | 7.522 | 6.177 | 0.564 | 2.55 | 0.463 | 0.191 | 2.95 | NEMSOK - Object Layer Attributes #1, Kód prvku: SN07.02.0001; Object Layer Attributes #1, Podlaží: 1.PP; Object Layer Attributes #1, Požární odolnost: bez požadavku; Object Layer Attributes #1, Funkce (venkovní): Ne; Object Layer Attributes #1, Statická funkce: Ne; Object Layer Attributes #1, Vlhkostní namáhání oboustranné: Ne; Object Layer Attributes #1, Tloušťka opláštění: 2×12,5; Object Layer Attributes #1, Typ SDK desky: vysokopevnostní+bílá; Object Layer Attributes #1, Způsob opláštění: Jednostranné; Object Layer Attributes #1, Tloušťka izolace (2): 0; Object Layer Attributes #1, Objemová hmotnost izolace: 0; Object Layer Attributes #1, Typ profilu pro SDK: CW 50; Object Layer Attributes #1, Rozteč rastru: 625
SDK ŠACHTOVÁ STĚNA/SDK OPL. S PO | Půdorys 1.PP | SDK ŠACHTOVÁ STĚNA/SDK OPL. S PO 0.075 m |  | SDK ŠACHTOVÁ STĚNA/SDK OPL. S PO |  | 1364HWa0798472973 | m3 | Celá stěna | Nový | Suché stavební práce | SDK ŠACHTOVÁ STĚNA/SDK OPL. S PO | no | 1364Stě0798472974 | m3 | Stěna |  | 0.075 | 3.909 | 3.763 | 0.293 | 1.325 | 0.282 | 0.099 | 2.95 | NEMSOK - Object Layer Attributes #1, Kód prvku: SN07.02.0001; Object Layer Attributes #1, Podlaží: 1.PP; Object Layer Attributes #1, Požární odolnost: bez požadavku; Object Layer Attributes #1, Funkce (venkovní): Ne; Object Layer Attributes #1, Statická funkce: Ne; Object Layer Attributes #1, Vlhkostní namáhání oboustranné: Ne; Object Layer Attributes #1, Tloušťka opláštění: 2×12,5; Object Layer Attributes #1, Typ SDK desky: vysokopevnostní+bílá; Object Layer Attributes #1, Způsob opláštění: Jednostranné; Object Layer Attributes #1, Tloušťka izolace (2): 0; Object Layer Attributes #1, Objemová hmotnost izolace: 0; Object Layer Attributes #1, Typ profilu pro SDK: CW 50; Object Layer Attributes #1, Rozteč rastru: 625
SDK ŠACHTOVÁ STĚNA/SDK OPL. S PO | Půdorys 1.PP | SDK ŠACHTOVÁ STĚNA/SDK OPL. S PO 0.075 m |  | SDK ŠACHTOVÁ STĚNA/SDK OPL. S PO |  | 1364HWa0798472981 | m3 | Celá stěna | Nový | Suché stavební práce | SDK ŠACHTOVÁ STĚNA/SDK OPL. S PO | no | 1364Stě0798472982 | m3 | Stěna |  | 0.075 | 1.328 | 1.328 | 0.1 | 0.45 | 0.1 | 0.034 | 2.95 | NEMSOK - Object Layer Attributes #1, Kód prvku: SN07.02.0001; Object Layer Attributes #1, Podlaží: 1.PP; Object Layer Attributes #1, Požární odolnost: bez požadavku; Object Layer Attributes #1, Funkce (venkovní): Ne; Object Layer Attributes #1, Statická funkce: Ne; Object Layer Attributes #1, Vlhkostní namáhání oboustranné: Ne; Object Layer Attributes #1, Tloušťka opláštění: 2×12,5; Object Layer Attributes #1, Typ SDK desky: vysokopevnostní+bílá; Object Layer Attributes #1, Způsob opláštění: Jednostranné; Object Layer Attributes #1, Tloušťka izolace (2): 0; Object Layer Attributes #1, Objemová hmotnost izolace: 0; Object Layer Attributes #1, Typ profilu pro SDK: CW 50; Object Layer Attributes #1, Rozteč rastru: 625
SDK ŠACHTOVÁ STĚNA/SDK OPL. S PO | Půdorys 1.PP | SDK ŠACHTOVÁ STĚNA/SDK OPL. S PO 0.075 m |  | SDK ŠACHTOVÁ STĚNA/SDK OPL. S PO |  | 1364HWa0798473599 | m3 | Celá stěna | Nový | Suché stavební práce | SDK ŠACHTOVÁ STĚNA/SDK OPL. S PO | no | 1364Stě0798473600 | m3 | Stěna |  | 0.075 | 2.434 | 2.434 | 0.183 | 0.825 | 0.183 | 0.062 | 2.95 | NEMSOK - Object Layer Attributes #1, Kód prvku: SN07.02.0001; Object Layer Attributes #1, Podlaží: 1.PP; Object Layer Attributes #1, Požární odolnost: bez požadavku; Object Layer Attributes #1, Funkce (venkovní): Ne; Object Layer Attributes #1, Statická funkce: Ne; Object Layer Attributes #1, Vlhkostní namáhání oboustranné: Ne; Object Layer Attributes #1, Tloušťka opláštění: 2×12,5; Object Layer Attributes #1, Typ SDK desky: vysokopevnostní+bílá; Object Layer Attributes #1, Způsob opláštění: Jednostranné; Object Layer Attributes #1, Tloušťka izolace (2): 0; Object Layer Attributes #1, Objemová hmotnost izolace: 0; Object Layer Attributes #1, Typ profilu pro SDK: CW 50; Object Layer Attributes #1, Rozteč rastru: 625
SDK ŠACHTOVÁ STĚNA/SDK OPL. S PO | Půdorys 1.PP | SDK ŠACHTOVÁ STĚNA/SDK OPL. S PO 0.075 m |  | SDK ŠACHTOVÁ STĚNA/SDK OPL. S PO |  | 1364HWa0798473604 | m3 | Celá stěna | Nový | Suché stavební práce | SDK ŠACHTOVÁ STĚNA/SDK OPL. S PO | no | 1364Stě0798473605 | m3 | Stěna |  | 0.075 | 1.475 | 1.435 | 0.111 | 0.5 | 0.108 | 0.037 | 2.95 | NEMSOK - Object Layer Attributes #1, Kód prvku: SN07.02.0001; Object Layer Attributes #1, Podlaží: 1.PP; Object Layer Attributes #1, Požární odolnost: bez požadavku; Object Layer Attributes #1, Funkce (venkovní): Ne; Object Layer Attributes #1, Statická funkce: Ne; Object Layer Attributes #1, Vlhkostní namáhání oboustranné: Ne; Object Layer Attributes #1, Tloušťka opláštění: 2×12,5; Object Layer Attributes #1, Typ SDK desky: vysokopevnostní+bílá; Object Layer Attributes #1, Způsob opláštění: Jednostranné; Object Layer Attributes #1, Tloušťka izolace (2): 0; Object Layer Attributes #1, Objemová hmotnost izolace: 0; Object Layer Attributes #1, Typ profilu pro SDK: CW 50; Object Layer Attributes #1, Rozteč rastru: 625
SDK - 1 KCE + DVOJITÉ OPLÁŠTĚNÍ | Půdorys 1.PP | SDK - 1 KCE + DVOJITÉ OPLÁŠTĚNÍ 0.15 m |  | SDK - 1 KCE + DVOJITÉ OPLÁŠTĚNÍ |  | 1364HWa0798473915 | m3 | Celá stěna | Nový | Suché stavební práce | SDK - 1 KCE + DVOJITÉ OPLÁŠTĚNÍ | no | 1364Stě0798473917 | m3 | Stěna |  | 0.15 | 4.27 | 4.27 | 0.641 | 1.4 | 0.641 | 0.21 | 3.05 | NEMSOK - Object Layer Attributes #1, Kód prvku: SN07.02.0001; Object Layer Attributes #1, Podlaží: 1.PP; Object Layer Attributes #1, Požární odolnost: EI 60; Object Layer Attributes #1, Funkce (venkovní): Ne; Object Layer Attributes #1, Statická funkce: Ne; Object Layer Attributes #1, Vážená stavební neprůzvučnost: 54; Object Layer Attributes #1, Vlhkostní namáhání oboustranné: Ne; Object Layer Attributes #1, Tloušťka opláštění: 2×12,5; Object Layer Attributes #1, Typ SDK desky: vysokopevnostní+bílá; Object Layer Attributes #1, Způsob opláštění: Oboustranné; Object Layer Attributes #1, Tloušťka izolace (2): 100; Object Layer Attributes #1, Objemová hmotnost izolace: 25; Object Layer Attributes #1, Typ profilu pro SDK: CW 100; Object Layer Attributes #1, Rozteč rastru: 625
SDK - 2 KCE + DVOJITÉ OPLÁŠTĚNÍ | Půdorys 1.PP | SDK - 2 KCE + DVOJITÉ OPLÁŠTĚNÍ 0.35 m |  | SDK - 2 KCE + DVOJITÉ OPLÁŠTĚNÍ |  | 1364HWa0798476502 | m3 | Celá stěna | Nový | Suché stavební práce | SDK - 2 KCE + DVOJITÉ OPLÁŠTĚNÍ | no | 1364Stě0798476503 | m3 | Stěna |  | 0.35 | 3.126 | 3.126 | 1.094 | 1.025 | 1.094 | 0.359 | 3.05 | NEMSOK - Object Layer Attributes #1, Kód prvku: SN07.02.0001; Object Layer Attributes #1, Podlaží: 1.PP; Object Layer Attributes #1, Požární odolnost: EI 60; Object Layer Attributes #1, Funkce (venkovní): Ne; Object Layer Attributes #1, Statická funkce: Ne; Object Layer Attributes #1, Vážená stavební neprůzvučnost: 54; Object Layer Attributes #1, Vlhkostní namáhání oboustranné: Ne; Object Layer Attributes #1, Tloušťka opláštění: 2×12,5; Object Layer Attributes #1, Typ SDK desky: vysokopevnostní+bílá; Object Layer Attributes #1, Způsob opláštění: Oboustranné; Object Layer Attributes #1, Tloušťka izolace (2): 100; Object Layer Attributes #1, Objemová hmotnost izolace: 25; Object Layer Attributes #1, Typ profilu pro SDK: 2× CW 100; Object Layer Attributes #1, Rozteč rastru: 625
SDK ŠACHTOVÁ STĚNA/SDK OPL. S PO | Půdorys 1.PP | SDK ŠACHTOVÁ STĚNA/SDK OPL. S PO 0.075 m |  | SDK ŠACHTOVÁ STĚNA/SDK OPL. S PO |  | 1364HWa0798476666 | m3 | Celá stěna | Nový | Suché stavební práce | SDK ŠACHTOVÁ STĚNA/SDK OPL. S PO | no | 1364Stě0798476667 | m3 | Stěna |  | 0.075 | 3.702 | 3.556 | 0.278 | 1.255 | 0.267 | 0.094 | 2.95 | NEMSOK - Object Layer Attributes #1, Kód prvku: SN07.02.0001; Object Layer Attributes #1, Podlaží: 1.PP; Object Layer Attributes #1, Požární odolnost: bez požadavku; Object Layer Attributes #1, Funkce (venkovní): Ne; Object Layer Attributes #1, Statická funkce: Ne; Object Layer Attributes #1, Vlhkostní namáhání oboustranné: Ne; Object Layer Attributes #1, Tloušťka opláštění: 2×12,5; Object Layer Attributes #1, Typ SDK desky: vysokopevnostní+bílá; Object Layer Attributes #1, Způsob opláštění: Jednostranné; Object Layer Attributes #1, Tloušťka izolace (2): 0; Object Layer Attributes #1, Objemová hmotnost izolace: 0; Object Layer Attributes #1, Typ profilu pro SDK: CW 50; Object Layer Attributes #1, Rozteč rastru: 625
SDK OPL. PROFESÍ/SDK OPL. BEZ PO | Půdorys 1.PP | SDK OPL. PROFESÍ/SDK OPL. BEZ PO 0.075 m |  | SDK OPL. PROFESÍ/SDK OPL. BEZ PO |  | 1364HWa0798476792 | m3 | Celá stěna | Nový | Suché stavební práce | SDK OPL. PROFESÍ/SDK OPL. BEZ PO | no | 1364Stě0798476793 | m3 | Stěna |  | 0.075 | 1.235 | 1.235 | 0.093 | 0.405 | 0.093 | 0.03 | 3.05 | NEMSOK - Object Layer Attributes #1, Kód prvku: SN07.02.0001; Object Layer Attributes #1, Podlaží: 1.PP; Object Layer Attributes #1, Požární odolnost: bez požadavku; Object Layer Attributes #1, Funkce (venkovní): Ne; Object Layer Attributes #1, Statická funkce: Ne; Object Layer Attributes #1, Vlhkostní namáhání oboustranné: Ne; Object Layer Attributes #1, Tloušťka opláštění: 2×12,5; Object Layer Attributes #1, Typ SDK desky: impregnovaná; Object Layer Attributes #1, Způsob opláštění: Jednostranné; Object Layer Attributes #1, Tloušťka izolace (2): 0; Object Layer Attributes #1, Objemová hmotnost izolace: 0; Object Layer Attributes #1, Typ profilu pro SDK: CW 50; Object Layer Attributes #1, Rozteč rastru: 625
SDK - 1 KCE + DVOJITÉ OPLÁŠTĚNÍ | Půdorys 1.PP | SDK - 1 KCE + DVOJITÉ OPLÁŠTĚNÍ 0.125 m |  | SDK - 1 KCE + DVOJITÉ OPLÁŠTĚNÍ |  | 1364HWa0798476852 | m3 | Celá stěna | Nový | Suché stavební práce | SDK - 1 KCE + DVOJITÉ OPLÁŠTĚNÍ | no | 1364Stě0798476853 | m3 | Stěna |  | 0.125 | 5.947 | 5.948 | 0.743 | 1.95 | 0.743 | 0.244 | 3.05 | NEMSOK - Object Layer Attributes #1, Kód prvku: SN07.02.0001; Object Layer Attributes #1, Podlaží: 1.PP; Object Layer Attributes #1, Požární odolnost: EI 60; Object Layer Attributes #1, Funkce (venkovní): Ne; Object Layer Attributes #1, Statická funkce: Ne; Object Layer Attributes #1, Vážená stavební neprůzvučnost: 54; Object Layer Attributes #1, Vlhkostní namáhání oboustranné: Ne; Object Layer Attributes #1, Tloušťka opláštění: 2×12,5; Object Layer Attributes #1, Typ SDK desky: vysokopevnostní+bílá; Object Layer Attributes #1, Způsob opláštění: Oboustranné; Object Layer Attributes #1, Tloušťka izolace (2): 75; Object Layer Attributes #1, Objemová hmotnost izolace: 25; Object Layer Attributes #1, Typ profilu pro SDK: CW 75; Object Layer Attributes #1, Rozteč rastru: 625
SDK - 1 KCE + DVOJITÉ OPLÁŠTĚNÍ | Půdorys 1.PP | SDK - 1 KCE + DVOJITÉ OPLÁŠTĚNÍ 0.125 m |  | SDK - 1 KCE + DVOJITÉ OPLÁŠTĚNÍ |  | 1364HWa0798494984 | m3 | Celá stěna | Nový | Suché stavební práce | SDK - 1 KCE + DVOJITÉ OPLÁŠTĚNÍ | no | 1364Stě0798495914 | m3 | Stěna |  | 0.125 | 11.285 | 11.17 | 1.411 | 3.7 | 1.396 | 0.463 | 3.05 | NEMSOK - Object Layer Attributes #1, Kód prvku: SN07.02.0001; Object Layer Attributes #1, Podlaží: 1.PP; Object Layer Attributes #1, Požární odolnost: EI 60; Object Layer Attributes #1, Funkce (venkovní): Ne; Object Layer Attributes #1, Statická funkce: Ne; Object Layer Attributes #1, Vážená stavební neprůzvučnost: 54; Object Layer Attributes #1, Vlhkostní namáhání oboustranné: Ne; Object Layer Attributes #1, Tloušťka opláštění: 2×12,5; Object Layer Attributes #1, Typ SDK desky: vysokopevnostní+bílá; Object Layer Attributes #1, Způsob opláštění: Oboustranné; Object Layer Attributes #1, Tloušťka izolace (2): 75; Object Layer Attributes #1, Objemová hmotnost izolace: 25; Object Layer Attributes #1, Typ profilu pro SDK: CW 75; Object Layer Attributes #1, Rozteč rastru: 625
SDK - 1 KCE + DVOJITÉ OPLÁŠTĚNÍ | Půdorys 1.PP | SDK - 1 KCE + DVOJITÉ OPLÁŠTĚNÍ 0.125 m |  | SDK - 1 KCE + DVOJITÉ OPLÁŠTĚNÍ |  | 1364HWa0798494986 | m3 | Celá stěna | Nový | Suché stavební práce | SDK - 1 KCE + DVOJITÉ OPLÁŠTĚNÍ | no | 1364Stě0798495226 | m3 | Stěna |  | 0.125 | 2.745 | 2.745 | 0.343 | 0.9 | 0.343 | 0.112 | 3.05 | NEMSOK - Object Layer Attributes #1, Kód prvku: SN07.02.0001; Object Layer Attributes #1, Podlaží: 1.PP; Object Layer Attributes #1, Požární odolnost: EI 60; Object Layer Attributes #1, Funkce (venkovní): Ne; Object Layer Attributes #1, Statická funkce: Ne; Object Layer Attributes #1, Vážená stavební neprůzvučnost: 54; Object Layer Attributes #1, Vlhkostní namáhání oboustranné: Ne; Object Layer Attributes #1, Tloušťka opláštění: 2×12,5; Object Layer Attributes #1, Typ SDK desky: vysokopevnostní+bílá; Object Layer Attributes #1, Způsob opláštění: Oboustranné; Object Layer Attributes #1, Tloušťka izolace (2): 75; Object Layer Attributes #1, Objemová hmotnost izolace: 25; Object Layer Attributes #1, Typ profilu pro SDK: CW 75; Object Layer Attributes #1, Rozteč rastru: 625
SDK - 1 KCE + DVOJITÉ OPLÁŠTĚNÍ | Půdorys 1.PP | SDK - 1 KCE + DVOJITÉ OPLÁŠTĚNÍ 0.15 m |  | SDK - 1 KCE + DVOJITÉ OPLÁŠTĚNÍ |  | 1364HWa0798495645 | m3 | Celá stěna | Nový | Suché stavební práce | SDK - 1 KCE + DVOJITÉ OPLÁŠTĚNÍ | no | 1364Stě0798495837 | m3 | Stěna |  | 0.15 | 16.737 | 16.738 | 2.511 | 5.15 | 2.511 | 0.772 | 3.25 | NEMSOK - Object Layer Attributes #1, Kód prvku: SN07.02.0001; Object Layer Attributes #1, Podlaží: 1.PP; Object Layer Attributes #1, Požární odolnost: EI 60; Object Layer Attributes #1, Funkce (venkovní): Ne; Object Layer Attributes #1, Statická funkce: Ne; Object Layer Attributes #1, Vážená stavební neprůzvučnost: 54; Object Layer Attributes #1, Vlhkostní namáhání oboustranné: Ne; Object Layer Attributes #1, Tloušťka opláštění: 2×12,5; Object Layer Attributes #1, Typ SDK desky: vysokopevnostní+bílá; Object Layer Attributes #1, Způsob opláštění: Oboustranné; Object Layer Attributes #1, Tloušťka izolace (2): 100; Object Layer Attributes #1, Objemová hmotnost izolace: 25; Object Layer Attributes #1, Typ profilu pro SDK: CW 100; Object Layer Attributes #1, Rozteč rastru: 625
SDK - 1 KCE + DVOJITÉ OPLÁŠTĚNÍ | Půdorys 1.PP | SDK - 1 KCE + DVOJITÉ OPLÁŠTĚNÍ 0.15 m |  | SDK - 1 KCE + DVOJITÉ OPLÁŠTĚNÍ |  | 1364HWa0798495646 | m3 | Celá stěna | Nový | Suché stavební práce | SDK - 1 KCE + DVOJITÉ OPLÁŠTĚNÍ | no | 1364Stě0798495729 | m3 | Stěna |  | 0.15 | 10.72 | 8.327 | 1.608 | 3.35 | 1.249 | 0.503 | 3.2 | NEMSOK - Object Layer Attributes #1, Kód prvku: SN07.02.0001; Object Layer Attributes #1, Podlaží: 1.PP; Object Layer Attributes #1, Požární odolnost: EI 60; Object Layer Attributes #1, Funkce (venkovní): Ne; Object Layer Attributes #1, Statická funkce: Ne; Object Layer Attributes #1, Vážená stavební neprůzvučnost: 54; Object Layer Attributes #1, Vlhkostní namáhání oboustranné: Ne; Object Layer Attributes #1, Tloušťka opláštění: 2×12,5; Object Layer Attributes #1, Typ SDK desky: vysokopevnostní+bílá; Object Layer Attributes #1, Způsob opláštění: Oboustranné; Object Layer Attributes #1, Tloušťka izolace (2): 100; Object Layer Attributes #1, Objemová hmotnost izolace: 25; Object Layer Attributes #1, Typ profilu pro SDK: CW 100; Object Layer Attributes #1, Rozteč rastru: 625
SDK - 1 KCE + DVOJITÉ OPLÁŠTĚNÍ | Půdorys 1.PP | SDK - 1 KCE + DVOJITÉ OPLÁŠTĚNÍ 0.15 m |  | SDK - 1 KCE + DVOJITÉ OPLÁŠTĚNÍ |  | 1364HWa0798495649 | m3 | Celá stěna | Nový | Suché stavební práce | SDK - 1 KCE + DVOJITÉ OPLÁŠTĚNÍ | no | 1364Stě0798495777 | m3 | Stěna |  | 0.15 | 15.52 | 15.44 | 2.328 | 4.85 | 2.316 | 0.728 | 3.2 | NEMSOK - Object Layer Attributes #1, Kód prvku: SN07.02.0001; Object Layer Attributes #1, Podlaží: 1.PP; Object Layer Attributes #1, Požární odolnost: EI 60; Object Layer Attributes #1, Funkce (venkovní): Ne; Object Layer Attributes #1, Statická funkce: Ne; Object Layer Attributes #1, Vážená stavební neprůzvučnost: 54; Object Layer Attributes #1, Vlhkostní namáhání oboustranné: Ne; Object Layer Attributes #1, Tloušťka opláštění: 2×12,5; Object Layer Attributes #1, Typ SDK desky: vysokopevnostní+bílá; Object Layer Attributes #1, Způsob opláštění: Oboustranné; Object Layer Attributes #1, Tloušťka izolace (2): 100; Object Layer Attributes #1, Objemová hmotnost izolace: 25; Object Layer Attributes #1, Typ profilu pro SDK: CW 100; Object Layer Attributes #1, Rozteč rastru: 625
SDK - 1 KCE + DVOJITÉ OPLÁŠTĚNÍ | Půdorys 1.PP | SDK - 1 KCE + DVOJITÉ OPLÁŠTĚNÍ 0.15 m |  | SDK - 1 KCE + DVOJITÉ OPLÁŠTĚNÍ |  | 1364HWa0798495650 | m3 | Celá stěna | Nový | Suché stavební práce | SDK - 1 KCE + DVOJITÉ OPLÁŠTĚNÍ | no | 1364Stě0798495781 | m3 | Stěna |  | 0.15 | 20.384 | 13.145 | 3.058 | 6.37 | 1.972 | 0.955 | 3.2 | NEMSOK - Object Layer Attributes #1, Kód prvku: SN07.02.0001; Object Layer Attributes #1, Podlaží: 1.PP; Object Layer Attributes #1, Požární odolnost: EI 60; Object Layer Attributes #1, Funkce (venkovní): Ne; Object Layer Attributes #1, Statická funkce: Ne; Object Layer Attributes #1, Vážená stavební neprůzvučnost: 54; Object Layer Attributes #1, Vlhkostní namáhání oboustranné: Ne; Object Layer Attributes #1, Tloušťka opláštění: 2×12,5; Object Layer Attributes #1, Typ SDK desky: vysokopevnostní+bílá; Object Layer Attributes #1, Způsob opláštění: Oboustranné; Object Layer Attributes #1, Tloušťka izolace (2): 100; Object Layer Attributes #1, Objemová hmotnost izolace: 25; Object Layer Attributes #1, Typ profilu pro SDK: CW 100; Object Layer Attributes #1, Rozteč rastru: 625
SDK - 1 KCE + DVOJITÉ OPLÁŠTĚNÍ | Půdorys 1.PP | SDK - 1 KCE + DVOJITÉ OPLÁŠTĚNÍ 0.15 m |  | SDK - 1 KCE + DVOJITÉ OPLÁŠTĚNÍ |  | 1364HWa0798495751 | m3 | Celá stěna | Nový | Suché stavební práce | SDK - 1 KCE + DVOJITÉ OPLÁŠTĚNÍ | no | 1364Stě0798495775 | m3 | Stěna |  | 0.15 | 20.8 | 20.76 | 3.12 | 6.5 | 3.114 | 0.975 | 3.2 | NEMSOK - Object Layer Attributes #1, Kód prvku: SN07.02.0001; Object Layer Attributes #1, Podlaží: 1.PP; Object Layer Attributes #1, Požární odolnost: EI 60; Object Layer Attributes #1, Funkce (venkovní): Ne; Object Layer Attributes #1, Statická funkce: Ne; Object Layer Attributes #1, Vážená stavební neprůzvučnost: 54; Object Layer Attributes #1, Vlhkostní namáhání oboustranné: Ne; Object Layer Attributes #1, Tloušťka opláštění: 2×12,5; Object Layer Attributes #1, Typ SDK desky: vysokopevnostní+bílá; Object Layer Attributes #1, Způsob opláštění: Oboustranné; Object Layer Attributes #1, Tloušťka izolace (2): 100; Object Layer Attributes #1, Objemová hmotnost izolace: 25; Object Layer Attributes #1, Typ profilu pro SDK: CW 100; Object Layer Attributes #1, Rozteč rastru: 625
SDK - 1 KCE + DVOJITÉ OPLÁŠTĚNÍ | Půdorys 1.PP | SDK - 1 KCE + DVOJITÉ OPLÁŠTĚNÍ 0.15 m |  | SDK - 1 KCE + DVOJITÉ OPLÁŠTĚNÍ |  | 1364HWa0798498691 | m3 | Celá stěna | Nový | Suché stavební práce | SDK - 1 KCE + DVOJITÉ OPLÁŠTĚNÍ | no | 1364Stě0798498692 | m3 | Stěna |  | 0.15 | 5.348 | 2.63 | 0.802 | 1.671 | 0.395 | 0.251 | 3.2 | NEMSOK - Object Layer Attributes #1, Kód prvku: SN07.02.0001; Object Layer Attributes #1, Podlaží: 1.PP; Object Layer Attributes #1, Požární odolnost: EI 60; Object Layer Attributes #1, Funkce (venkovní): Ne; Object Layer Attributes #1, Statická funkce: Ne; Object Layer Attributes #1, Vážená stavební neprůzvučnost: 54; Object Layer Attributes #1, Vlhkostní namáhání oboustranné: Ne; Object Layer Attributes #1, Tloušťka opláštění: 2×12,5; Object Layer Attributes #1, Typ SDK desky: vysokopevnostní+bílá; Object Layer Attributes #1, Způsob opláštění: Oboustranné; Object Layer Attributes #1, Tloušťka izolace (2): 100; Object Layer Attributes #1, Objemová hmotnost izolace: 25; Object Layer Attributes #1, Typ profilu pro SDK: CW 100; Object Layer Attributes #1, Rozteč rastru: 625
SDK INSTAL. PŘDSTĚNA VYSOKÁ | Půdorys 1.PP | SDK INSTAL. PŘDSTĚNA VYSOKÁ 0.15 m |  | SDK INSTAL. PŘDSTĚNA VYSOKÁ |  | 1364HWa0798527117 | m3 | Celá stěna | Nový | Suché stavební práce | SDK INSTAL. PŘDSTĚNA VYSOKÁ | no | 1364Stě0798527118 | m3 | Stěna |  | 0.15 | 3.797 | 3.797 | 0.57 | 1.245 | 0.57 | 0.187 | 3.05 | NEMSOK - Object Layer Attributes #1, Kód prvku: SN07.02.0001; Object Layer Attributes #1, Podlaží: 1.PP; Object Layer Attributes #1, Požární odolnost: bez požadavku; Object Layer Attributes #1, Funkce (venkovní): Ne; Object Layer Attributes #1, Statická funkce: Ne; Object Layer Attributes #1, Vlhkostní namáhání oboustranné: Ne; Object Layer Attributes #1, Tloušťka opláštění: 2×12,5; Object Layer Attributes #1, Typ SDK desky: impregnovaná; Object Layer Attributes #1, Způsob opláštění: Jednostranné; Object Layer Attributes #1, Tloušťka izolace (2): 0; Object Layer Attributes #1, Objemová hmotnost izolace: 0; Object Layer Attributes #1, Typ profilu pro SDK: CW 50; Object Layer Attributes #1, Rozteč rastru: 625
SDK - 1 KCE + DVOJITÉ OPLÁŠTĚNÍ | Půdorys 1.PP | SDK - 1 KCE + DVOJITÉ OPLÁŠTĚNÍ 0.125 m |  | SDK - 1 KCE + DVOJITÉ OPLÁŠTĚNÍ |  | 1364HWa0798528612 | m3 | Celá stěna | Nový | Suché stavební práce | SDK - 1 KCE + DVOJITÉ OPLÁŠTĚNÍ | no | 1364Stě0798528613 | m3 | Stěna |  | 0.125 | 4.331 | 4.296 | 0.541 | 1.42 | 0.537 | 0.178 | 3.05 | NEMSOK - Object Layer Attributes #1, Kód prvku: SN07.02.0001; Object Layer Attributes #1, Podlaží: 1.PP; Object Layer Attributes #1, Požární odolnost: EI 60; Object Layer Attributes #1, Funkce (venkovní): Ne; Object Layer Attributes #1, Statická funkce: Ne; Object Layer Attributes #1, Vážená stavební neprůzvučnost: 54; Object Layer Attributes #1, Vlhkostní namáhání oboustranné: Ne; Object Layer Attributes #1, Tloušťka opláštění: 2×12,5; Object Layer Attributes #1, Typ SDK desky: vysokopevnostní+bílá; Object Layer Attributes #1, Způsob opláštění: Oboustranné; Object Layer Attributes #1, Tloušťka izolace (2): 75; Object Layer Attributes #1, Objemová hmotnost izolace: 25; Object Layer Attributes #1, Typ profilu pro SDK: CW 75; Object Layer Attributes #1, Rozteč rastru: 625
SDK - 1 KCE + DVOJITÉ OPLÁŠTĚNÍ | Půdorys 1.PP | SDK - 1 KCE + DVOJITÉ OPLÁŠTĚNÍ 0.125 m |  | SDK - 1 KCE + DVOJITÉ OPLÁŠTĚNÍ |  | 1364HWa0798528622 | m3 | Celá stěna | Nový | Suché stavební práce | SDK - 1 KCE + DVOJITÉ OPLÁŠTĚNÍ | no | 1364Stě0798528623 | m3 | Stěna |  | 0.125 | 6.634 | 6.634 | 0.829 | 2.175 | 0.829 | 0.272 | 3.05 | NEMSOK - Object Layer Attributes #1, Kód prvku: SN07.02.0001; Object Layer Attributes #1, Podlaží: 1.PP; Object Layer Attributes #1, Požární odolnost: EI 60; Object Layer Attributes #1, Funkce (venkovní): Ne; Object Layer Attributes #1, Statická funkce: Ne; Object Layer Attributes #1, Vážená stavební neprůzvučnost: 54; Object Layer Attributes #1, Vlhkostní namáhání oboustranné: Ne; Object Layer Attributes #1, Tloušťka opláštění: 2×12,5; Object Layer Attributes #1, Typ SDK desky: vysokopevnostní+bílá; Object Layer Attributes #1, Způsob opláštění: Oboustranné; Object Layer Attributes #1, Tloušťka izolace (2): 75; Object Layer Attributes #1, Objemová hmotnost izolace: 25; Object Layer Attributes #1, Typ profilu pro SDK: CW 75; Object Layer Attributes #1, Rozteč rastru: 625
SDK - 2 KCE + DVOJITÉ OPLÁŠTĚNÍ | Půdorys 1.PP | SDK - 2 KCE + DVOJITÉ OPLÁŠTĚNÍ 0.25 m |  | SDK - 2 KCE + DVOJITÉ OPLÁŠTĚNÍ |  | 1364HWa0798529298 | m3 | Celá stěna | Nový | Suché stavební práce | SDK - 2 KCE + DVOJITÉ OPLÁŠTĚNÍ | no | 1364Stě0798529299 | m3 | Stěna |  | 0.25 | 3.508 | 3.417 | 0.877 | 1.15 | 0.854 | 0.288 | 3.05 | NEMSOK - Object Layer Attributes #1, Kód prvku: SN07.02.0001; Object Layer Attributes #1, Podlaží: 1.PP; Object Layer Attributes #1, Požární odolnost: EI 60; Object Layer Attributes #1, Funkce (venkovní): Ne; Object Layer Attributes #1, Statická funkce: Ne; Object Layer Attributes #1, Vážená stavební neprůzvučnost: 54; Object Layer Attributes #1, Vlhkostní namáhání oboustranné: Ne; Object Layer Attributes #1, Tloušťka opláštění: 2×12,5; Object Layer Attributes #1, Typ SDK desky: vysokopevnostní+bílá; Object Layer Attributes #1, Způsob opláštění: Oboustranné; Object Layer Attributes #1, Tloušťka izolace (2): 100; Object Layer Attributes #1, Objemová hmotnost izolace: 25; Object Layer Attributes #1, Typ profilu pro SDK: 2× CW 100; Object Layer Attributes #1, Rozteč rastru: 625
SDK ŠACHTOVÁ STĚNA/SDK OPL. S PO | Půdorys 1.PP | SDK ŠACHTOVÁ STĚNA/SDK OPL. S PO 0.075 m |  | SDK ŠACHTOVÁ STĚNA/SDK OPL. S PO |  | 1364HWa0798585489 | m3 | Celá stěna | Nový | Suché stavební práce | SDK ŠACHTOVÁ STĚNA/SDK OPL. S PO | no | 1364Stě0798585490 | m3 | Stěna |  | 0.075 | 1.991 | 1.991 | 0.149 | 0.675 | 0.149 | 0.051 | 2.95 | NEMSOK - Object Layer Attributes #1, Kód prvku: SN07.02.0001; Object Layer Attributes #1, Podlaží: 1.PP; Object Layer Attributes #1, Požární odolnost: bez požadavku; Object Layer Attributes #1, Funkce (venkovní): Ne; Object Layer Attributes #1, Statická funkce: Ne; Object Layer Attributes #1, Vlhkostní namáhání oboustranné: Ne; Object Layer Attributes #1, Tloušťka opláštění: 2×12,5; Object Layer Attributes #1, Typ SDK desky: vysokopevnostní+bílá; Object Layer Attributes #1, Způsob opláštění: Jednostranné; Object Layer Attributes #1, Tloušťka izolace (2): 0; Object Layer Attributes #1, Objemová hmotnost izolace: 0; Object Layer Attributes #1, Typ profilu pro SDK: CW 50; Object Layer Attributes #1, Rozteč rastru: 625
SDK ŠACHTOVÁ STĚNA/SDK OPL. S PO | Půdorys 1.PP | SDK ŠACHTOVÁ STĚNA/SDK OPL. S PO 0.075 m |  | SDK ŠACHTOVÁ STĚNA/SDK OPL. S PO |  | 1364HWa0798585495 | m3 | Celá stěna | Nový | Suché stavební práce | SDK ŠACHTOVÁ STĚNA/SDK OPL. S PO | no | 1364Stě0798585496 | m3 | Stěna |  | 0.075 | 0.811 | 0.811 | 0.061 | 0.275 | 0.061 | 0.021 | 2.95 | NEMSOK - Object Layer Attributes #1, Kód prvku: SN07.02.0001; Object Layer Attributes #1, Podlaží: 1.PP; Object Layer Attributes #1, Požární odolnost: bez požadavku; Object Layer Attributes #1, Funkce (venkovní): Ne; Object Layer Attributes #1, Statická funkce: Ne; Object Layer Attributes #1, Vlhkostní namáhání oboustranné: Ne; Object Layer Attributes #1, Tloušťka opláštění: 2×12,5; Object Layer Attributes #1, Typ SDK desky: vysokopevnostní+bílá; Object Layer Attributes #1, Způsob opláštění: Jednostranné; Object Layer Attributes #1, Tloušťka izolace (2): 0; Object Layer Attributes #1, Objemová hmotnost izolace: 0; Object Layer Attributes #1, Typ profilu pro SDK: CW 50; Object Layer Attributes #1, Rozteč rastru: 625
SDK OPL. PROFESÍ/SDK OPL. BEZ PO | Půdorys 1.PP | SDK OPL. PROFESÍ/SDK OPL. BEZ PO 0.075 m |  | SDK OPL. PROFESÍ/SDK OPL. BEZ PO |  | 1364HWa0000008062 | m3 | Celá stěna | Nový | Suché stavební práce | SDK OPL. PROFESÍ/SDK OPL. BEZ PO | no | 1364Stě0000008063 | m3 | Stěna |  | 0.075 | 1.22 | 1.22 | 0.091 | 0.4 | 0.091 | 0.03 | 3.05 | NEMSOK - Object Layer Attributes #1, Kód prvku: SN07.02.0001; Object Layer Attributes #1, Podlaží: 1.PP; Object Layer Attributes #1, Požární odolnost: bez požadavku; Object Layer Attributes #1, Funkce (venkovní): Ne; Object Layer Attributes #1, Statická funkce: Ne; Object Layer Attributes #1, Vlhkostní namáhání oboustranné: Ne; Object Layer Attributes #1, Tloušťka opláštění: 2×12,5; Object Layer Attributes #1, Typ SDK desky: impregnovaná; Object Layer Attributes #1, Způsob opláštění: Jednostranné; Object Layer Attributes #1, Tloušťka izolace (2): 0; Object Layer Attributes #1, Objemová hmotnost izolace: 0; Object Layer Attributes #1, Typ profilu pro SDK: CW 50; Object Layer Attributes #1, Rozteč rastru: 625
ZDIVO Z CDm | Půdorys 1.NP | ZDIVO Z CDm 0.5 m | 1 | ZDIVO Z CDm | A | 1452HWa0000000007 | m3 | Celá stěna | Stávající | Zednické práce | ZDIVO Z CDm | yes | 1452Stě0000001505 | m3 | Stěna | 0 | 0.5 | 18.258 | 18.258 | 9.129 | 5.45 | 9.129 | 2.725 | 3.35
ZDIVO Z CDm | Půdorys 1.NP | ZDIVO Z CDm 0.5 m | 1 | ZDIVO Z CDm | A | 1452HWa0000000009 | m3 | Celá stěna | Stávající | Zednické práce | ZDIVO Z CDm | yes | 1452Stě0000001509 | m3 | Stěna | 0 | 0.5 | 11.725 | 11.725 | 5.863 | 3.5 | 5.863 | 1.75 | 3.35
ZDIVO Z CDm | Půdorys 1.NP | ZDIVO Z CDm 0.5 m |  | ZDIVO Z CDm | A | 1452HWa0000001475 | m3 | Celá stěna | Stávající | Zednické práce | ZDIVO Z CDm | yes | 1452Stě0000001495 | m3 | Stěna | 0 | 0.5 | 33.5 | 29.72 | 16.75 | 10 | 14.86 | 5 | 3.35
ZELEZOBETONOVÁ KCE | Půdorys 1.NP | ZELEZOBETONOVÁ KCE 0.3 m | 1 | ZELEZOBETONOVÁ KCE | A | 1452HWa0000003847 | m3 | Celá stěna | Stávající | Betonářské práce | ZELEZOBETONOVÁ KCE |  | 1452Stě0000003848 | m3 | Stěna | 0 | 0.3 | 25.92 | 25.92 | 7.776 | 7.2 | 7.776 | 2.16 | 3.6
ZELEZOBETONOVÁ KCE | Půdorys 1.NP | ZELEZOBETONOVÁ KCE 0.3 m | 1 | ZELEZOBETONOVÁ KCE | A | 1452HWa0000003863 | m3 | Celá stěna | Stávající | Betonářské práce | ZELEZOBETONOVÁ KCE |  | 1452Stě0000003867 | m3 | Stěna | 0 | 0.3 | 19.44 | 19.44 | 5.832 | 5.4 | 5.832 | 1.62 | 3.6
ZELEZOBETONOVÁ KCE | Půdorys 1.NP | ZELEZOBETONOVÁ KCE 0.3 m | 1 | ZELEZOBETONOVÁ KCE | A | 1452HWa0000003877 | m3 | Celá stěna | Stávající | Betonářské práce | ZELEZOBETONOVÁ KCE |  | 1452Stě0000003895 | m3 | Stěna | 0 | 0.3 | 3.6 | 3.6 | 1.08 | 1 | 1.08 | 0.3 | 3.6
ZELEZOBETONOVÁ KCE | Půdorys 1.NP | ZELEZOBETONOVÁ KCE 0.3 m | 1 | ZELEZOBETONOVÁ KCE | A | 1452HWa0000003896 | m3 | Celá stěna | Stávající | Betonářské práce | ZELEZOBETONOVÁ KCE |  | 1452Stě0000003901 | m3 | Stěna | 0 | 0.3 | 3.6 | 3.6 | 1.08 | 1 | 1.08 | 0.3 | 3.6
ZELEZOBETONOVÁ KCE | Půdorys 1.NP | ZELEZOBETONOVÁ KCE 0.3 m | 1 | ZELEZOBETONOVÁ KCE | A | 1452HWa0000004743 | m3 | Celá stěna | Stávající | Betonářské práce | ZELEZOBETONOVÁ KCE |  | 1452Stě0000004750 | m3 | Stěna | 0 | 0.3 | 3.672 | 3.672 | 1.102 | 1.02 | 1.102 | 0.306 | 3.6
ZELEZOBETONOVÁ KCE | Půdorys 1.NP | ZELEZOBETONOVÁ KCE 0.32 m | 1 | ZELEZOBETONOVÁ KCE | A | 1452HWa0000003879 | m3 | Celá stěna | Stávající | Betonářské práce | ZELEZOBETONOVÁ KCE |  | 1452Stě0000003967 | m3 | Stěna | 0 | 0.32 | 89.1 | 63.9 | 28.512 | 24.75 | 20.026 | 7.92 | 3.6
ZELEZOBETONOVÁ KCE | Půdorys 1.NP | ZELEZOBETONOVÁ KCE 0.3 m | 1 | ZELEZOBETONOVÁ KCE | A | 1452HWa0798418226 | m3 | Celá stěna | Stávající | Betonářské práce | ZELEZOBETONOVÁ KCE |  | 1452Stě0798418227 | m3 | Stěna | 0 | 0.3 | 3.672 | 3.672 | 1.102 | 1.02 | 1.102 | 0.306 | 3.6
ZELEZOBETONOVÁ KCE | Půdorys 1.NP | ZELEZOBETONOVÁ KCE 0.3 m | 1 | ZELEZOBETONOVÁ KCE | A | 1452HWa0000004768 | m3 | Celá stěna | Stávající | Betonářské práce | ZELEZOBETONOVÁ KCE |  | 1452Stě0000004769 | m3 | Stěna | 0 | 0.3 | 49.32 | 40.815 | 14.796 | 13.7 | 12.245 | 4.11 | 3.6
ZELEZOBETONOVÁ KCE | Půdorys 1.NP | ZELEZOBETONOVÁ KCE 0.3 m | 1 | ZELEZOBETONOVÁ KCE | A | 1452HWa0000004745 | m3 | Celá stěna | Stávající | Betonářské práce | ZELEZOBETONOVÁ KCE |  | 1452Stě0000004748 | m3 | Stěna | 0 | 0.3 | 20.52 | 17.37 | 6.156 | 5.7 | 5.211 | 1.71 | 3.6
ZELEZOBETONOVÁ KCE | Půdorys 1.NP | ZELEZOBETONOVÁ KCE 0.32 m | 1 | ZELEZOBETONOVÁ KCE | A | 1452HWa0000004127 | m3 | Celá stěna | Stávající | Betonářské práce | ZELEZOBETONOVÁ KCE |  | 1452Stě0000004161 | m3 | Stěna | 0 | 0.32 | 86.4 | 61.2 | 27.648 | 24 | 19.209 | 7.68 | 3.6
PLYNOSILIKÁT | Půdorys 1.NP | PLYNOSILIKÁT 0.32 m | 1 | PLYNOSILIKÁT | REI 180 | 1452HWa0798422884 | m3 | Celá stěna | Stávající | Zednické práce | PLYNOSILIKÁT | no | 1452Stě0798422885 | m3 | Stěna | 0.541 | 0.32 | 3.24 | 3.21 | 1.037 | 0.9 | 1.027 | 0.288 | 3.6 | Pset_WallCommon - AcousticRating: 48 dB
PLYNOSILIKÁT | Půdorys 1.NP | PLYNOSILIKÁT 0.3 m |  | PLYNOSILIKÁT | REI 180 | 1452HWa0798419382 | m3 | Celá stěna | Stávající | Zednické práce | PLYNOSILIKÁT | no | 1452Stě0798419384 | m3 | Stěna | 0.541 | 0.3 | 2.448 | 2.44 | 0.734 | 0.68 | 0.732 | 0.204 | 3.6 | Pset_WallCommon - AcousticRating: 48 dB
ZDIVO Z CDm | Půdorys 1.NP | ZDIVO Z CDm 0.25 m | 1 | ZDIVO Z CDm | A | 1452HWa0798431240 | m3 | Celá stěna | Stávající | Zednické práce | ZDIVO Z CDm |  | 1452Stě0798431241 | m3 | Stěna | 0 | 0.25 | 15.494 | 13.07 | 3.873 | 4.625 | 3.267 | 1.156 | 3.35
YTONG 100 | Půdorys 1.NP | YTONG 100 0.1 m | 1 | YTONG 100 | EI 120 | 1452HWa0798432562 | m3 | Celá stěna | Stávající | Zednické práce | YTONG 100 |  | 1452Stě0798432563 | m2 | Stěna | 1.111 | 0.1 | 1.424 | 1.424 | 0.142 | 0.425 | 0.142 | 0.042 | 3.35 | Pset_WallCommon - AcousticRating: 37 dB
ZDIVO Z CDm | Půdorys 1.NP | ZDIVO Z CDm 0.15 m | 1 | ZDIVO Z CDm | A | 1452HWa0798432574 | m3 | Celá stěna | Stávající | Zednické práce | ZDIVO Z CDm | yes | 1452Stě0798432575 | m3 | Stěna | 0 | 0.15 | 0.335 | 0.335 | 0.05 | 0.1 | 0.05 | 0.015 | 3.35
ZDIVO Z CDm | Půdorys 1.NP | ZDIVO Z CDm 0.25 m | 1 | ZDIVO Z CDm | A | 1452HWa0798434318 | m3 | Celá stěna | Stávající | Zednické práce | ZDIVO Z CDm | yes | 1452Stě0798435843 | m3 | Stěna | 0 | 0.25 | 16.75 | 9.744 | 4.188 | 5 | 2.436 | 1.25 | 3.35
ZDIVO Z CDm | Půdorys 1.NP | ZDIVO Z CDm 0.35 m | 1 | ZDIVO Z CDm | A | 1452HWa0798435836 | m3 | Celá stěna | Stávající | Zednické práce | ZDIVO Z CDm | yes | 1452Stě0798435850 | m3 | Stěna | 0 | 0.35 | 1.34 | 1.34 | 0.469 | 0.4 | 0.469 | 0.14 | 3.35
ZDIVO Z CDm | Půdorys 1.NP | ZDIVO Z CDm 0.35 m | 1 | ZDIVO Z CDm | A | 1452HWa0798435838 | m3 | Celá stěna | Stávající | Zednické práce | ZDIVO Z CDm | yes | 1452Stě0798435845 | m3 | Stěna | 0 | 0.35 | 1.34 | 1.34 | 0.469 | 0.4 | 0.469 | 0.14 | 3.35
ZDIVO Z CDm | Půdorys 1.NP | ZDIVO Z CDm 0.2 m | 1 | ZDIVO Z CDm | A | 1452HWa0798436127 | m3 | Celá stěna | Stávající | Zednické práce | ZDIVO Z CDm |  | 1452Stě0798436132 | m3 | Stěna | 0 | 0.2 | 0.737 | 0.737 | 0.147 | 0.22 | 0.147 | 0.044 | 3.35
ZELEZOBETONOVÁ KCE | Půdorys 1.NP | ZELEZOBETONOVÁ KCE 0.2 m | 1 | ZELEZOBETONOVÁ KCE | A | 1452HWa0798419765 | m3 | Celá stěna | Stávající | Betonářské práce | ZELEZOBETONOVÁ KCE |  | 1452Stě0798419766 | m3 | Stěna | 0 | 0.2 | 16.08 | 16.08 | 3.216 | 4.8 | 3.216 | 0.96 | 3.35
ZELEZOBETONOVÁ KCE | Půdorys 1.NP | ZELEZOBETONOVÁ KCE 0.2 m |  | ZELEZOBETONOVÁ KCE | A | 1452HWa0798434314 | m3 | Celá stěna | Stávající | Betonářské práce | ZELEZOBETONOVÁ KCE | yes | 1452Stě0798435848 | m3 | Stěna | 0 | 0.2 | 10.05 | 10.05 | 2.01 | 3 | 2.01 | 0.6 | 3.35
ZELEZOBETONOVÁ KCE | Půdorys 1.NP | ZELEZOBETONOVÁ KCE 0.2 m |  | ZELEZOBETONOVÁ KCE | A | 1452HWa0798421506 | m3 | Celá stěna | Stávající | Betonářské práce | ZELEZOBETONOVÁ KCE | yes | 1452Stě0798421507 | m3 | Stěna | 0 | 0.2 | 11.055 | 11.055 | 2.211 | 3.3 | 2.211 | 0.66 | 3.35
ZELEZOBETONOVÁ KCE | Půdorys 1.NP | ZELEZOBETONOVÁ KCE 0.2 m |  | ZELEZOBETONOVÁ KCE | A | 1452HWa0798422152 | m3 | Celá stěna | Stávající | Betonářské práce | ZELEZOBETONOVÁ KCE | yes | 1452Stě0798422153 | m3 | Stěna | 0 | 0.2 | 18.09 | 18.09 | 3.618 | 5.4 | 3.618 | 1.08 | 3.35
ZELEZOBETONOVÁ KCE | Půdorys 1.NP | ZELEZOBETONOVÁ KCE 0.2 m | 1 | ZELEZOBETONOVÁ KCE | A | 1452HWa0798422097 | m3 | Celá stěna | Stávající | Betonářské práce | ZELEZOBETONOVÁ KCE |  | 1452Stě0798422098 | m3 | Stěna | 0 | 0.2 | 6.365 | 6.365 | 1.273 | 1.9 | 1.273 | 0.38 | 3.35
ZELEZOBETONOVÁ KCE | Půdorys 1.NP | ZELEZOBETONOVÁ KCE 0.2 m | 1 | ZELEZOBETONOVÁ KCE | A | 1452HWa0798422126 | m3 | Celá stěna | Stávající | Betonářské práce | ZELEZOBETONOVÁ KCE |  | 1452Stě0798422127 | m3 | Stěna | 0 | 0.2 | 5.025 | 5.025 | 1.005 | 1.5 | 1.005 | 0.3 | 3.35
ZELEZOBETONOVÁ KCE | Půdorys 1.NP | ZELEZOBETONOVÁ KCE 0.2 m | 1 | ZELEZOBETONOVÁ KCE | A | 1452HWa0798436323 | m3 | Celá stěna | Stávající | Betonářské práce | ZELEZOBETONOVÁ KCE |  | 1452Stě0798436325 | m3 | Stěna | 0 | 0.2 | 6.365 | 6.365 | 1.273 | 1.9 | 1.273 | 0.38 | 3.35
ZELEZOBETONOVÁ KCE | Půdorys 1.NP | ZELEZOBETONOVÁ KCE 0.2 m |  | ZELEZOBETONOVÁ KCE | A | 1452HWa0798421711 | m3 | Celá stěna | Stávající | Betonářské práce | ZELEZOBETONOVÁ KCE | yes | 1452Stě0798421712 | m3 | Stěna | 0 | 0.2 | 16.08 | 16.08 | 3.216 | 4.8 | 3.216 | 0.96 | 3.35
ZELEZOBETONOVÁ KCE | Půdorys 1.NP | ZELEZOBETONOVÁ KCE 0.2 m | 1 | ZELEZOBETONOVÁ KCE | A | 1452HWa0798436367 | m3 | Celá stěna | Stávající | Betonářské práce | ZELEZOBETONOVÁ KCE | yes | 1452Stě0798436369 | m3 | Stěna | 0 | 0.2 | 16.08 | 16.08 | 3.216 | 4.8 | 3.216 | 0.96 | 3.35
ZELEZOBETONOVÁ KCE | Půdorys 1.NP | ZELEZOBETONOVÁ KCE 0.2 m |  | ZELEZOBETONOVÁ KCE | A | 1452HWa0798419775 | m3 | Celá stěna | Stávající | Betonářské práce | ZELEZOBETONOVÁ KCE | yes | 1452Stě0798419785 | m3 | Stěna | 0 | 0.2 | 12.06 | 12.06 | 2.412 | 3.6 | 2.412 | 0.72 | 3.35
ZELEZOBETONOVÁ KCE | Půdorys 1.NP | ZELEZOBETONOVÁ KCE 0.2 m | 1 | ZELEZOBETONOVÁ KCE | A | 1452HWa0798421357 | m3 | Celá stěna | Stávající | Betonářské práce | ZELEZOBETONOVÁ KCE | yes | 1452Stě0798421358 | m3 | Stěna | 0 | 0.2 | 12.06 | 12.06 | 2.412 | 3.6 | 2.412 | 0.72 | 3.35
ZELEZOBETONOVÁ KCE | Půdorys 1.NP | ZELEZOBETONOVÁ KCE 0.2 m | 1 | ZELEZOBETONOVÁ KCE | A | 1452HWa0798436358 | m3 | Celá stěna | Stávající | Betonářské práce | ZELEZOBETONOVÁ KCE | yes | 1452Stě0798436360 | m3 | Stěna | 0 | 0.2 | 13.4 | 13.4 | 2.68 | 4 | 2.68 | 0.8 | 3.35
ZELEZOBETONOVÁ KCE | Půdorys 1.NP | ZELEZOBETONOVÁ KCE 0.2 m |  | ZELEZOBETONOVÁ KCE | A | 1452HWa0798421334 | m3 | Celá stěna | Stávající | Betonářské práce | ZELEZOBETONOVÁ KCE | yes | 1452Stě0798421335 | m3 | Stěna | 0 | 0.2 | 16.75 | 16.75 | 3.35 | 5 | 3.35 | 1 | 3.35
ZELEZOBETONOVÁ KCE | Půdorys 1.NP | ZELEZOBETONOVÁ KCE 0.32 m | 1 | ZELEZOBETONOVÁ KCE | A | 1452HWa0798418589 | m3 | Celá stěna | Stávající | Betonářské práce | ZELEZOBETONOVÁ KCE |  | 1452Stě0798418590 | m3 | Stěna | 0 | 0.32 | 66.42 | 45.356 | 21.254 | 18.45 | 14.139 | 5.904 | 3.6
ZELEZOBETONOVÁ KCE | Půdorys 1.NP | ZELEZOBETONOVÁ KCE 0.3 m | 1 | ZELEZOBETONOVÁ KCE | A | 1452HWa0000004877 | m3 | Celá stěna | Stávající | Betonářské práce | ZELEZOBETONOVÁ KCE |  | 1452Stě0000004878 | m3 | Stěna | 0 | 0.3 | 3.78 | 3.78 | 1.134 | 1.05 | 1.134 | 0.315 | 3.6
ZELEZOBETONOVÁ KCE | Půdorys 1.NP | ZELEZOBETONOVÁ KCE 0.3 m | 1 | ZELEZOBETONOVÁ KCE | A | 1452HWa0000004882 | m3 | Celá stěna | Stávající | Betonářské práce | ZELEZOBETONOVÁ KCE |  | 1452Stě0000004883 | m3 | Stěna | 0 | 0.3 | 3.672 | 3.672 | 1.102 | 1.02 | 1.102 | 0.306 | 3.6
ZELEZOBETONOVÁ KCE | Půdorys 1.NP | ZELEZOBETONOVÁ KCE 0.3 m | 1 | ZELEZOBETONOVÁ KCE | A | 1452HWa0798419416 | m3 | Celá stěna | Stávající | Betonářské práce | ZELEZOBETONOVÁ KCE |  | 1452Stě0798419419 | m3 | Stěna | 0 | 0.3 | 3.78 | 3.78 | 1.134 | 1.05 | 1.134 | 0.315 | 3.6
ZELEZOBETONOVÁ KCE | Půdorys 1.NP | ZELEZOBETONOVÁ KCE 0.3 m | 1 | ZELEZOBETONOVÁ KCE | A | 1452HWa0000004895 | m3 | Celá stěna | Stávající | Betonářské práce | ZELEZOBETONOVÁ KCE | no | 1452Stě0000004897 | m3 | Stěna | 0 | 0.3 | 3.672 | 3.672 | 1.102 | 1.02 | 1.102 | 0.306 | 3.6
ZDIVO Z CDm | Půdorys 1.NP | ZDIVO Z CDm 0.48 m | 1 | ZDIVO Z CDm | A | 1452HWa0798436125 | m3 | Celá stěna | Stávající | Zednické práce | ZDIVO Z CDm |  | 1452Stě0798436130 | m3 | Stěna | 0 | 0.48 | 1.575 | 1.44 | 0.756 | 0.438 | 0.756 | 0.21 | 3.6
ZELEZOBETONOVÁ KCE | Půdorys 1.NP | ZELEZOBETONOVÁ KCE 0.3 m | 1 | ZELEZOBETONOVÁ KCE | A | 1452HWa0798418267 | m3 | Celá stěna | Stávající | Betonářské práce | ZELEZOBETONOVÁ KCE |  | 1452Stě0798418268 | m3 | Stěna | 0 | 0.3 | 10.8 | 10.8 | 3.24 | 3 | 3.24 | 0.9 | 3.6
ZELEZOBETONOVÁ KCE | Půdorys 1.NP | ZELEZOBETONOVÁ KCE 0.3 m | 1 | ZELEZOBETONOVÁ KCE | A | 1452HWa0000004872 | m3 | Celá stěna | Stávající | Betonářské práce | ZELEZOBETONOVÁ KCE |  | 1452Stě0000004873 | m3 | Stěna | 0 | 0.3 | 20.34 | 20.275 | 6.102 | 5.65 | 6.083 | 1.695 | 3.6
ZDIVO Z CDm | Půdorys 1.NP | ZDIVO Z CDm 0.3 m | 1 | ZDIVO Z CDm | A | 1452HWa0798441050 | m3 | Celá stěna | Stávající | Zednické práce | ZDIVO Z CDm |  | 1452Stě0798441051 | m3 | Stěna | 0 | 0.3 | 1.548 | 1.728 | 0.464 | 0.43 | 0.464 | 0.129 | 3.6
STÁVAJÍCÍ KCE | Půdorys 1.NP | STÁVAJÍCÍ KCE 0.4 m |  | STÁVAJÍCÍ KCE | REI 180 | 1452HWa0798429739 | m3 | Celá stěna | Stávající | Zednické práce | STÁVAJÍCÍ KCE | yes | 1452Stě0798429740 | m3 | Stěna | 0.541 | 0.4 | 8.543 | 8.27 | 3.417 | 2.55 | 3.375 | 1.02 | 3.35 | Pset_WallCommon - AcousticRating: 48 dB
STÁVAJÍCÍ KCE | Půdorys 1.NP | STÁVAJÍC KCE 0.4 m | 1 | STÁVAJÍCÍ KCE | REI 180 | 1452HWa0798429886 | m3 | Celá stěna | Stávající | Zednické práce | STÁVAJÍC KCE | yes | 1452Stě0798429887 | m3 | Stěna | 0.541 | 0.4 | 10.72 | 11.295 | 4.288 | 3.2 | 4.25 | 1.28 | 3.35 | Pset_WallCommon - AcousticRating: 48 dB
ZDIVO Z CDm | Půdorys 1.NP | ZDIVO Z CDm 0.125 m | 1 | ZDIVO Z CDm | A | 1452HWa0798445581 | m3 | Celá stěna | Stávající | Zednické práce | ZDIVO Z CDm |  | 1452Stě0798445582 | m3 | Stěna | 0 | 0.125 | 1.005 | 1.005 | 0.126 | 0.3 | 0.126 | 0.037 | 3.35
ZDIVO Z CDm | Půdorys 1.NP | ZDIVO Z CDm 0.125 m |  | ZDIVO Z CDm | A | 1452HWa0798445645 | m3 | Celá stěna | Stávající | Zednické práce | ZDIVO Z CDm |  | 1452Stě0798445648 | m3 | Stěna | 0 | 0.125 | 10.083 | 10.083 | 1.26 | 2.725 | 1.26 | 0.341 | 3.7
ZDIVO Z CDm | Půdorys 1.NP | ZDIVO Z CDm 0.125 m |  | ZDIVO Z CDm | A | 1452HWa0798445570 | m3 | Celá stěna | Stávající | Zednické práce | ZDIVO Z CDm |  | 1452Stě0798445571 | m3 | Stěna | 0 | 0.125 | 1.172 | 1.173 | 0.147 | 0.35 | 0.147 | 0.044 | 3.35
ZDIVO Z CDm | Půdorys 1.NP | ZDIVO Z CDm 0.125 m | 1 | ZDIVO Z CDm | A | 1452HWa0798445711 | m3 | Celá stěna | Stávající | Zednické práce | ZDIVO Z CDm | yes | 1452Stě0798445725 | m3 | Stěna | 0 | 0.125 | 1.675 | 1.675 | 0.209 | 0.5 | 0.209 | 0.062 | 3.35
ZDIVO Z CDm | Půdorys 1.NP | ZDIVO Z CDm 0.125 m | 1 | ZDIVO Z CDm | A | 1452HWa0798445713 | m3 | Celá stěna | Stávající | Zednické práce | ZDIVO Z CDm | yes | 1452Stě0798445718 | m3 | Stěna | 0 | 0.125 | 0.335 | 0.335 | 0.042 | 0.1 | 0.042 | 0.013 | 3.35
ZDIVO Z CDm | Půdorys 1.NP | ZDIVO Z CDm 0.125 m | 1 | ZDIVO Z CDm | A | 1452HWa0798445715 | m3 | Celá stěna | Stávající | Zednické práce | ZDIVO Z CDm | yes | 1452Stě0798445723 | m3 | Stěna | 0 | 0.125 | 3.015 | 3.015 | 0.377 | 0.9 | 0.377 | 0.113 | 3.35
ZDIVO Z CDm | Půdorys 1.NP | ZDIVO Z CDm 0.125 m | 1 | ZDIVO Z CDm | A | 1452HWa0798445753 | m3 | Celá stěna | Stávající | Zednické práce | ZDIVO Z CDm | yes | 1452Stě0798445760 | m3 | Stěna | 0 | 0.125 | 4.355 | 3.865 | 0.544 | 1.3 | 0.483 | 0.163 | 3.35
PÓROBETONOVÉ ZDIVO | Půdorys 1.NP | PÓROBETONOVÉ ZDIVO 0.3 m | 1 | PÓROBETONOVÉ ZDIVO | REI 180 | 1452HWa0798445946 | m3 | Celá stěna | Stávající | Zednické práce | PÓROBETONOVÉ ZDIVO |  | 1452Stě0798445947 | m3 | Stěna | 0.541 | 0.3 | 1.44 | 1.44 | 0.432 | 0.4 | 0.432 | 0.12 | 3.6 | Pset_WallCommon - AcousticRating: 48 dB
PÓROBETONOVÉ ZDIVO | Půdorys 1.NP | PÓROBETONOVÉ ZDIVO 0.25 m | 1 | PÓROBETONOVÉ ZDIVO | REI 180 | 1452HWa0798445953 | m3 | Celá stěna | Stávající | Zednické práce | PÓROBETONOVÉ ZDIVO |  | 1452Stě0798445954 | m3 | Stěna | 0.541 | 0.25 | 1.8 | 1.775 | 0.45 | 0.5 | 0.444 | 0.125 | 3.6 | Pset_WallCommon - AcousticRating: 48 dB
ZDIVO Z CDm | Půdorys 1.NP | ZDIVO Z CDm 0.125 m | 1 | ZDIVO Z CDm | A | 1452HWa0798445977 | m3 | Celá stěna | Stávající | Zednické práce | ZDIVO Z CDm |  | 1452Stě0798445978 | m3 | Stěna | 0 | 0.125 | 3.417 | 3.417 | 0.427 | 1.02 | 0.427 | 0.127 | 3.35
ZDIVO Z CDm | Půdorys 1.NP | ZDIVO Z CDm 0.125 m | 1 | ZDIVO Z CDm | A | 1452HWa0798446083 | m3 | Celá stěna | Stávající | Zednické práce | ZDIVO Z CDm | yes | 1452Stě0798446144 | m3 | Stěna | 0 | 0.125 | 4.104 | 3.604 | 0.513 | 1.225 | 0.45 | 0.153 | 3.35
ZDIVO Z CDm | Půdorys 1.NP | ZDIVO Z CDm 0.125 m | 1 | ZDIVO Z CDm | A | 1452HWa0798446085 | m3 | Celá stěna | Stávající | Zednické práce | ZDIVO Z CDm | yes | 1452Stě0798446112 | m3 | Stěna | 0 | 0.125 | 1.759 | 1.759 | 0.22 | 0.525 | 0.22 | 0.066 | 3.35
ZDIVO Z CDm | Půdorys 1.NP | ZDIVO Z CDm 0.125 m | 1 | ZDIVO Z CDm | A | 1452HWa0798446087 | m3 | Celá stěna | Stávající | Zednické práce | ZDIVO Z CDm | yes | 1452Stě0798446142 | m3 | Stěna | 0 | 0.125 | 3.685 | 3.685 | 0.461 | 1.1 | 0.461 | 0.138 | 3.35
ZELEZOBETONOVÁ KCE | Půdorys 1.NP | ZELEZOBETONOVÁ KCE 0.2 m | 1 | ZELEZOBETONOVÁ KCE | A | 1452HWa0798446073 | m3 | Celá stěna | Stávající | Betonářské práce | ZELEZOBETONOVÁ KCE | no | 1452Stě0798446074 | m3 | Stěna | 0 | 0.2 | 18.725 | 18.725 | 3.745 | 5.13 | 3.745 | 1.026 | 3.65 | Pset_WallCommon - LoadBearing: yes
ZDIVO Z CDm | Půdorys 1.NP | ZDIVO Z CDm 0.125 m | 1 | ZDIVO Z CDm | A | 1452HWa0798446265 | m3 | Celá stěna | Stávající | Zednické práce | ZDIVO Z CDm | yes | 1452Stě0798446266 | m3 | Stěna | 0 | 0.125 | 2.429 | 2.429 | 0.304 | 0.725 | 0.304 | 0.091 | 3.35
ZDIVO Z CDm | Půdorys 1.NP | ZDIVO Z CDm 0.125 m | 1 | ZDIVO Z CDm | A | 1452HWa0798446277 | m3 | Celá stěna | Stávající | Zednické práce | ZDIVO Z CDm | yes | 1452Stě0798446278 | m3 | Stěna | 0 | 0.125 | 3.015 | 3.015 | 0.377 | 0.9 | 0.377 | 0.113 | 3.35
PÓROBETONOVÉ ZDIVO | Půdorys 1.NP | PÓROBETONOVÉ ZDIVO 0.12 m | 1 | PÓROBETONOVÉ ZDIVO | EI 120 | 1452HWa0798446297 | m3 | Celá stěna | Stávající | Zednické práce | PÓROBETONOVÉ ZDIVO |  | 1452Stě0798446298 | m2 | Stěna | 1.111 | 0.12 | 13.651 | 13.651 | 1.638 | 4.075 | 1.638 | 0.489 | 3.35 | Pset_WallCommon - AcousticRating: 37 dB
PÓROBETONOVÉ ZDIVO | Půdorys 1.NP | PÓROBETONOVÉ ZDIVO 0.08 m | 1 | PÓROBETONOVÉ ZDIVO | EI 120 | 1452HWa0798446306 | m3 | Celá stěna | Stávající | Zednické práce | PÓROBETONOVÉ ZDIVO |  | 1452Stě0798446307 | m2 | Stěna | 1.111 | 0.08 | 11.993 | 11.993 | 0.959 | 3.58 | 0.959 | 0.286 | 3.35 | Pset_WallCommon - AcousticRating: 37 dB
PÓROBETONOVÉ ZDIVO | Půdorys 1.NP | PÓROBETONOVÉ ZDIVO 0.08 m | 1 | PÓROBETONOVÉ ZDIVO | EI 120 | 1452HWa0798446317 | m3 | Celá stěna | Stávající | Zednické práce | PÓROBETONOVÉ ZDIVO |  | 1452Stě0798446318 | m2 | Stěna | 1.111 | 0.08 | 11.993 | 11.993 | 0.959 | 3.58 | 0.959 | 0.286 | 3.35 | Pset_WallCommon - AcousticRating: 37 dB
ZDIVO Z CDm | Půdorys 1.NP | ZDIVO Z CDm 0.125 m | 1 | ZDIVO Z CDm | A | 1452HWa0798446414 | m3 | Celá stěna | Stávající | Zednické práce | ZDIVO Z CDm | yes | 1452Stě0798446415 | m3 | Stěna | 0 | 0.125 | 1.675 | 1.675 | 0.209 | 0.5 | 0.209 | 0.063 | 3.35
YTONG 150 | Půdorys 1.NP | YTONG 150 0.15 m | 1 | YTONG 150 | EI 180 | 1452HWa0798446467 | m3 | Celá stěna | Stávající | Zednické práce | YTONG 150 |  | 1452Stě0798446468 | m2 | Stěna | 0.794 | 0.15 | 13.651 | 13.651 | 2.048 | 4.075 | 2.048 | 0.611 | 3.35 | Pset_WallCommon - AcousticRating: 41 dB
ZDIVO Z CDm | Půdorys 1.NP | ZDIVO Z CDm 0.125 m | 1 | ZDIVO Z CDm | A | 1452HWa0798446476 | m3 | Celá stěna | Stávající | Zednické práce | ZDIVO Z CDm | yes | 1452Stě0798446477 | m3 | Stěna | 0 | 0.125 | 2.01 | 2.01 | 0.251 | 0.6 | 0.251 | 0.075 | 3.35
ZDIVO Z CDm | Půdorys 1.NP | ZDIVO Z CDm 0.125 m | 1 | ZDIVO Z CDm | A | 1452HWa0798446499 | m3 | Celá stěna | Stávající | Zednické práce | ZDIVO Z CDm | yes | 1452Stě0798446500 | m3 | Stěna | 0 | 0.125 | 2.596 | 2.596 | 0.325 | 0.775 | 0.325 | 0.097 | 3.35
ZDIVO Z CDm | Půdorys 1.NP | ZDIVO Z CDm 0.125 m | 1 | ZDIVO Z CDm | A | 1452HWa0798446489 | m3 | Celá stěna | Stávající | Zednické práce | ZDIVO Z CDm | yes | 1452Stě0798446490 | m3 | Stěna | 0 | 0.125 | 2.429 | 2.429 | 0.304 | 0.725 | 0.304 | 0.091 | 3.35
ZDIVO Z CDm | Půdorys 1.NP | ZDIVO Z CDm 0.125 m | 1 | ZDIVO Z CDm | A | 1452HWa0798446539 | m3 | Celá stěna | Stávající | Zednické práce | ZDIVO Z CDm | yes | 1452Stě0798446540 | m3 | Stěna | 0 | 0.125 | 1.507 | 1.508 | 0.188 | 0.45 | 0.188 | 0.056 | 3.35
ZDIVO Z CDm | Půdorys 1.NP | ZDIVO Z CDm 0.125 m | 1 | ZDIVO Z CDm | A | 1452HWa0798446549 | m3 | Celá stěna | Stávající | Zednické práce | ZDIVO Z CDm | yes | 1452Stě0798446550 | m3 | Stěna | 0 | 0.125 | 2.345 | 2.345 | 0.293 | 0.7 | 0.293 | 0.088 | 3.35
ZDIVO Z CDm | Půdorys 1.NP | ZDIVO Z CDm 0.125 m | 1 | ZDIVO Z CDm | A | 1452HWa0798446576 | m3 | Celá stěna | Stávající | Zednické práce | ZDIVO Z CDm | yes | 1452Stě0798446577 | m3 | Stěna | 0 | 0.125 | 1.106 | 1.106 | 0.138 | 0.33 | 0.138 | 0.041 | 3.35
ZDIVO Z CDm | Půdorys 1.NP | ZDIVO Z CDm 0.125 m | 1 | ZDIVO Z CDm | A | 1452HWa0798446586 | m3 | Celá stěna | Stávající | Zednické práce | ZDIVO Z CDm | yes | 1452Stě0798446587 | m3 | Stěna | 0 | 0.125 | 0.837 | 0.838 | 0.105 | 0.25 | 0.105 | 0.031 | 3.35
YTONG 150 | Půdorys 1.NP | YTONG 150 0.15 m | 1 | YTONG 150 | EI 180 | 1452HWa0798446638 | m3 | Celá stěna | Stávající | Zednické práce | YTONG 150 |  | 1452Stě0798446639 | m2 | Stěna | 0.794 | 0.15 | 13.082 | 13.082 | 1.962 | 3.905 | 1.962 | 0.586 | 3.35 | Pset_WallCommon - AcousticRating: 41 dB
ZDIVO Z CDm | Půdorys 1.NP | ZDIVO Z CDm 0.125 m | 1 | ZDIVO Z CDm | A | 1452HWa0798446685 | m3 | Celá stěna | Stávající | Zednické práce | ZDIVO Z CDm | yes | 1452Stě0798446686 | m3 | Stěna | 0 | 0.125 | 3.199 | 3.199 | 0.4 | 0.955 | 0.4 | 0.119 | 3.35
ZDIVO Z CDm | Půdorys 1.NP | ZDIVO Z CDm 0.125 m | 1 | ZDIVO Z CDm | A | 1452HWa0798446694 | m3 | Celá stěna | Stávající | Zednické práce | ZDIVO Z CDm | yes | 1452Stě0798446695 | m3 | Stěna | 0 | 0.125 | 1.759 | 1.759 | 0.22 | 0.525 | 0.22 | 0.066 | 3.35
ZDIVO Z CDm | Půdorys 1.NP | ZDIVO Z CDm 0.125 m | 1 | ZDIVO Z CDm | A | 1452HWa0798446706 | m3 | Celá stěna | Stávající | Zednické práce | ZDIVO Z CDm | yes | 1452Stě0798446707 | m3 | Stěna | 0 | 0.125 | 2.781 | 2.781 | 0.348 | 0.83 | 0.348 | 0.104 | 3.35
YTONG 150 | Půdorys 1.NP | YTONG 150 0.15 m | 1 | YTONG 150 | EI 180 | 1452HWa0798446741 | m3 | Celá stěna | Stávající | Zednické práce | YTONG 150 |  | 1452Stě0798446742 | m2 | Stěna | 0.794 | 0.15 | 11.976 | 11.976 | 1.796 | 3.575 | 1.796 | 0.536 | 3.35 | Pset_WallCommon - AcousticRating: 41 dB
ZDIVO Z CDm | Půdorys 1.NP | ZDIVO Z CDm 0.125 m | 1 | ZDIVO Z CDm | A | 1452HWa0798446754 | m3 | Celá stěna | Stávající | Zednické práce | ZDIVO Z CDm | yes | 1452Stě0798446755 | m3 | Stěna | 0 | 0.125 | 0.67 | 0.67 | 0.084 | 0.2 | 0.084 | 0.025 | 3.35
ZDIVO Z CDm | Půdorys 1.NP | ZDIVO Z CDm 0.125 m | 1 | ZDIVO Z CDm | A | 1452HWa0798446766 | m3 | Celá stěna | Stávající | Zednické práce | ZDIVO Z CDm | yes | 1452Stě0798446767 | m3 | Stěna | 0 | 0.125 | 2.01 | 2.01 | 0.251 | 0.6 | 0.251 | 0.075 | 3.35
ZELEZOBETONOVÁ KCE | Půdorys 1.NP | ZELEZOBETONOVÁ KCE 0.2 m | 1 | ZELEZOBETONOVÁ KCE | A | 1452HWa0798446778 | m3 | Celá stěna | Stávající | Betonářské práce | ZELEZOBETONOVÁ KCE | no | 1452Stě0798446779 | m3 | Stěna | 0 | 0.2 | 19.181 | 19.181 | 3.836 | 5.255 | 3.836 | 1.051 | 3.65 | Pset_WallCommon - LoadBearing: yes
ZDIVO Z CDm | Půdorys 1.NP | ZDIVO Z CDm 0.125 m | 1 | ZDIVO Z CDm | A | 1452HWa0798446234 | m3 | Celá stěna | Stávající | Zednické práce | ZDIVO Z CDm | yes | 1452Stě0798446235 | m3 | Stěna | 0 | 0.125 | 52.26 | 40.544 | 6.533 | 15.6 | 5.068 | 1.95 | 3.35
ZDIVO Z CDm | Půdorys 1.NP | ZDIVO Z CDm 0.125 m | 1 | ZDIVO Z CDm | A | 1452HWa0798446873 | m3 | Celá stěna | Stávající | Zednické práce | ZDIVO Z CDm | yes | 1452Stě0798446874 | m3 | Stěna | 0 | 0.125 | 4.104 | 3.384 | 0.513 | 1.225 | 0.423 | 0.153 | 3.35
ZDIVO Z CDm | Půdorys 1.NP | ZDIVO Z CDm 0.125 m | 1 | ZDIVO Z CDm | A | 1452HWa0798446883 | m3 | Celá stěna | Stávající | Zednické práce | ZDIVO Z CDm | yes | 1452Stě0798446884 | m3 | Stěna | 0 | 0.125 | 1.34 | 1.34 | 0.168 | 0.4 | 0.168 | 0.05 | 3.35
ZDIVO Z CDm | Půdorys 1.NP | ZDIVO Z CDm 0.125 m | 1 | ZDIVO Z CDm | A | 1452HWa0798446914 | m3 | Celá stěna | Stávající | Zednické práce | ZDIVO Z CDm | yes | 1452Stě0798446953 | m3 | Stěna | 0 | 0.125 | 2.68 | 2.68 | 0.335 | 0.8 | 0.335 | 0.1 | 3.35
ZDIVO Z CDm | Půdorys 1.NP | ZDIVO Z CDm 0.125 m | 1 | ZDIVO Z CDm | A | 1452HWa0798446916 | m3 | Celá stěna | Stávající | Zednické práce | ZDIVO Z CDm | yes | 1452Stě0798446943 | m3 | Stěna | 0 | 0.125 | 1.926 | 1.386 | 0.241 | 0.575 | 0.173 | 0.072 | 3.35
ZDIVO Z CDm | Půdorys 1.NP | ZDIVO Z CDm 0.125 m | 1 | ZDIVO Z CDm | A | 1452HWa0798446918 | m3 | Celá stěna | Stávající | Zednické práce | ZDIVO Z CDm | yes | 1452Stě0798446948 | m3 | Stěna | 0 | 0.125 | 2.261 | 2.261 | 0.283 | 0.675 | 0.283 | 0.084 | 3.35
ZDIVO Z CDm | Půdorys 1.NP | ZDIVO Z CDm 0.125 m | 1 | ZDIVO Z CDm | A | 1452HWa0798446920 | m3 | Celá stěna | Stávající | Zednické práce | ZDIVO Z CDm | yes | 1452Stě0798446955 | m3 | Stěna | 0 | 0.125 | 2.68 | 2.68 | 0.335 | 0.8 | 0.335 | 0.1 | 3.35
ZDIVO Z CDm | Půdorys 1.NP | ZDIVO Z CDm 0.125 m | 1 | ZDIVO Z CDm | A | 1452HWa0798446922 | m3 | Celá stěna | Stávající | Zednické práce | ZDIVO Z CDm | yes | 1452Stě0798446941 | m3 | Stěna | 0 | 0.125 | 1.926 | 1.386 | 0.241 | 0.575 | 0.173 | 0.072 | 3.35
ZDIVO Z CDm | Půdorys 1.NP | ZDIVO Z CDm 0.125 m | 1 | ZDIVO Z CDm | A | 1452HWa0798446924 | m3 | Celá stěna | Stávající | Zednické práce | ZDIVO Z CDm | yes | 1452Stě0798446951 | m3 | Stěna | 0 | 0.125 | 2.261 | 2.261 | 0.283 | 0.675 | 0.283 | 0.084 | 3.35
ZDIVO Z CDm | Půdorys 1.NP | ZDIVO Z CDm 0.125 m | 1 | ZDIVO Z CDm | A | 1452HWa0798447139 | m3 | Celá stěna | Stávající | Zednické práce | ZDIVO Z CDm | yes | 1452Stě0798447146 | m3 | Stěna | 0 | 0.125 | 3.266 | 2.766 | 0.408 | 0.975 | 0.346 | 0.122 | 3.35
ZDIVO Z CDm | Půdorys 1.NP | ZDIVO Z CDm 0.125 m | 1 | ZDIVO Z CDm | A | 1452HWa0798447141 | m3 | Celá stěna | Stávající | Zednické práce | ZDIVO Z CDm | yes | 1452Stě0798447147 | m3 | Stěna | 0 | 0.125 | 1.424 | 1.424 | 0.178 | 0.425 | 0.178 | 0.053 | 3.35
ZDIVO Z CDm | Půdorys 1.NP | ZDIVO Z CDm 0.125 m | 1 | ZDIVO Z CDm | A | 1452HWa0798447197 | m3 | Celá stěna | Stávající | Zednické práce | ZDIVO Z CDm | yes | 1452Stě0798447199 | m3 | Stěna | 0 | 0.125 | 14.154 | 12.336 | 1.769 | 4.225 | 1.542 | 0.528 | 3.35
YTONG 150 | Půdorys 1.NP | YTONG 150 0.15 m | 1 | YTONG 150 | EI 180 | 1452HWa0798447336 | m3 | Celá stěna | Stávající | Zednické práce | YTONG 150 |  | 1452Stě0798447337 | m2 | Stěna | 0.794 | 0.15 | 1.507 | 1.508 | 0.226 | 0.45 | 0.226 | 0.067 | 3.35 | Pset_WallCommon - AcousticRating: 41 dB
YTONG 125 | Půdorys 1.NP | YTONG 125 0.125 m | 1 | YTONG 125 | EI 180 | 1452HWa0798447614 | m3 | Celá stěna | Stávající | Zednické práce | YTONG 125 |  | 1452Stě0798447615 | m2 | Stěna | 0.926 | 0.125 | 5.36 | 5.36 | 0.67 | 1.6 | 0.67 | 0.2 | 3.35 | Pset_WallCommon - AcousticRating: 39 dB
YTONG 100 | Půdorys 1.NP | YTONG 100 0.1 m | 1 | YTONG 100 | EI 120 | 1452HWa0798447629 | m3 | Celá stěna | Stávající | Zednické práce | YTONG 100 |  | 1452Stě0798447630 | m2 | Stěna | 1.111 | 0.1 | 8.291 | 6.675 | 0.829 | 2.475 | 0.668 | 0.247 | 3.35 | Pset_WallCommon - AcousticRating: 37 dB
YTONG 100 | Půdorys 1.NP | YTONG 100 0.1 m | 1 | YTONG 100 | EI 120 | 1452HWa0798447639 | m3 | Celá stěna | Stávající | Zednické práce | YTONG 100 |  | 1452Stě0798447640 | m2 | Stěna | 1.111 | 0.1 | 8.291 | 8.291 | 0.829 | 2.475 | 0.829 | 0.247 | 3.35 | Pset_WallCommon - AcousticRating: 37 dB
YTONG 100 | Půdorys 1.NP | YTONG 100 0.1 m | 1 | YTONG 100 | EI 120 | 1452HWa0798447644 | m3 | Celá stěna | Stávající | Zednické práce | YTONG 100 |  | 1452Stě0798447645 | m2 | Stěna | 1.111 | 0.1 | 2.178 | 2.178 | 0.218 | 0.65 | 0.218 | 0.065 | 3.35 | Pset_WallCommon - AcousticRating: 37 dB
YTONG 100 | Půdorys 1.NP | YTONG 100 0.1 m | 1 | YTONG 100 | EI 120 | 1452HWa0798447654 | m3 | Celá stěna | Stávající | Zednické práce | YTONG 100 |  | 1452Stě0798447655 | m2 | Stěna | 1.111 | 0.1 | 5.863 | 4.247 | 0.586 | 1.75 | 0.425 | 0.175 | 3.35 | Pset_WallCommon - AcousticRating: 37 dB
ZDIVO Z CDm | Půdorys 1.NP | ZDIVO Z CDm 0.125 m | 1 | ZDIVO Z CDm | A | 1452HWa0798445999 | m3 | Celá stěna | Stávající | Zednické práce | ZDIVO Z CDm |  | 1452Stě0798446000 | m3 | Stěna | 0 | 0.125 | 16.08 | 16.08 | 2.01 | 4.8 | 2.01 | 0.6 | 3.35
YTONG 100 | Půdorys 1.NP | YTONG 100 0.1 m | 1 | YTONG 100 | EI 120 | 1452HWa0798447769 | m3 | Celá stěna | Stávající | Zednické práce | YTONG 100 |  | 1452Stě0798447770 | m2 | Stěna | 1.111 | 0.1 | 2.345 | 2.345 | 0.234 | 0.7 | 0.234 | 0.07 | 3.35 | Pset_WallCommon - AcousticRating: 37 dB
ZDIVO Z CDm | Půdorys 1.NP | ZDIVO Z CDm 0.125 m | 1 | ZDIVO Z CDm | A | 1452HWa0798447934 | m3 | Celá stěna | Stávající | Zednické práce | ZDIVO Z CDm |  | 1452Stě0798447935 | m3 | Stěna | 0 | 0.125 | 0.67 | 0.67 | 0.084 | 0.2 | 0.084 | 0.025 | 3.35
ZDIVO Z CDm | Půdorys 1.NP | ZDIVO Z CDm 0.125 m | 1 | ZDIVO Z CDm | A | 1452HWa0798447946 | m3 | Celá stěna | Stávající | Zednické práce | ZDIVO Z CDm |  | 1452Stě0798447947 | m3 | Stěna | 0 | 0.125 | 0.67 | 0.67 | 0.084 | 0.2 | 0.084 | 0.025 | 3.35
YTONG 100 | Půdorys 1.NP | YTONG 100 0.1 m | 1 | YTONG 100 | EI 120 | 1452HWa0798447958 | m3 | Celá stěna | Stávající | Zednické práce | YTONG 100 |  | 1452Stě0798447959 | m2 | Stěna | 1.111 | 0.1 | 1.675 | 1.675 | 0.168 | 0.5 | 0.168 | 0.05 | 3.35 | Pset_WallCommon - AcousticRating: 37 dB
YTONG | Půdorys 1.NP | YTONG 0.175 m | 1 | YTONG | EI 180 | 1452HWa0798447978 | m3 | Celá stěna | Stávající | Zednické práce | YTONG |  | 1452Stě0798447979 | m2 | Stěna | 0.794 | 0.175 | 1.593 | 1.593 | 0.279 | 0.455 | 0.279 | 0.08 | 3.5 | Pset_WallCommon - AcousticRating: 41 dB
YTONG 150 | Půdorys 1.NP | YTONG 150 0.15 m | 1 | YTONG 150 | EI 180 | 1452HWa0798447206 | m3 | Celá stěna | Stávající | Zednické práce | YTONG 150 |  | 1452Stě0798447207 | m2 | Stěna | 0.794 | 0.15 | 17.604 | 13.968 | 2.641 | 5.255 | 2.095 | 0.788 | 3.35 | Pset_WallCommon - AcousticRating: 41 dB
ZDIVO Z CDm | Půdorys 1.NP | ZDIVO Z CDm 0.125 m | 1 | ZDIVO Z CDm | A | 1452HWa0798447241 | m3 | Celá stěna | Stávající | Zednické práce | ZDIVO Z CDm | yes | 1452Stě0798447242 | m3 | Stěna | 0 | 0.125 | 3.182 | 3.183 | 0.398 | 0.95 | 0.398 | 0.119 | 3.35
ZDIVO Z CDm | Půdorys 1.NP | ZDIVO Z CDm 0.125 m | 1 | ZDIVO Z CDm | A | 1452HWa0798447254 | m3 | Celá stěna | Stávající | Zednické práce | ZDIVO Z CDm | yes | 1452Stě0798447255 | m3 | Stěna | 0 | 0.125 | 1.524 | 1.524 | 0.191 | 0.455 | 0.191 | 0.057 | 3.35
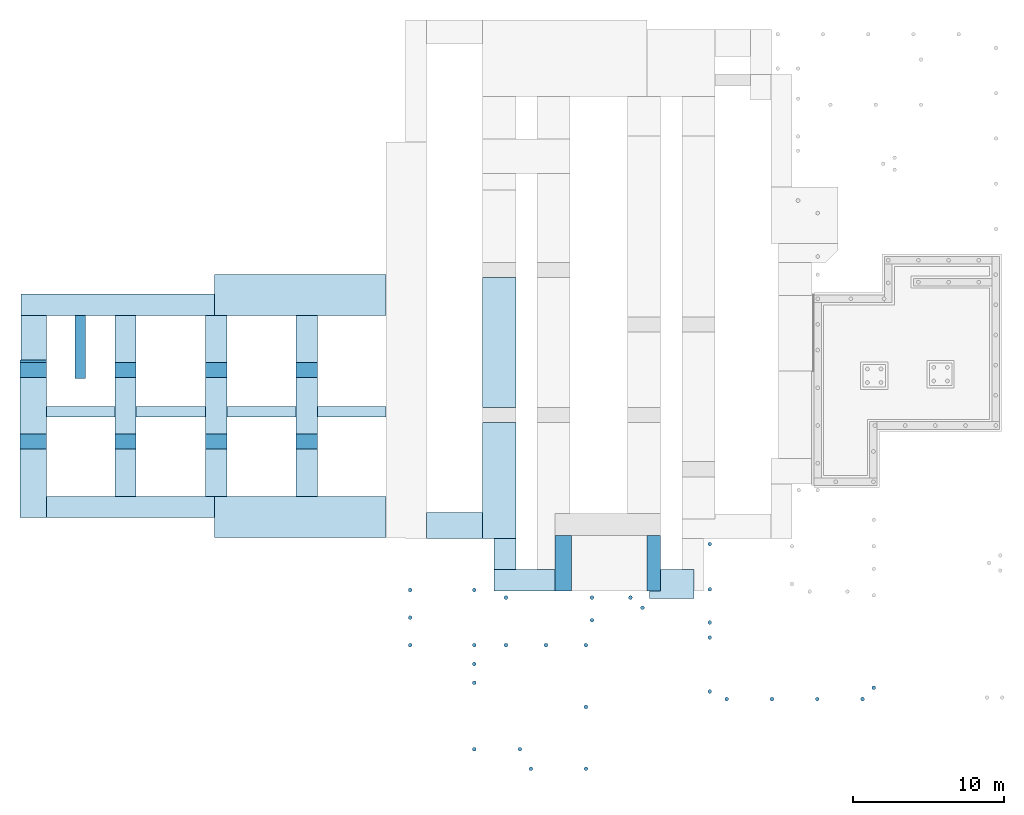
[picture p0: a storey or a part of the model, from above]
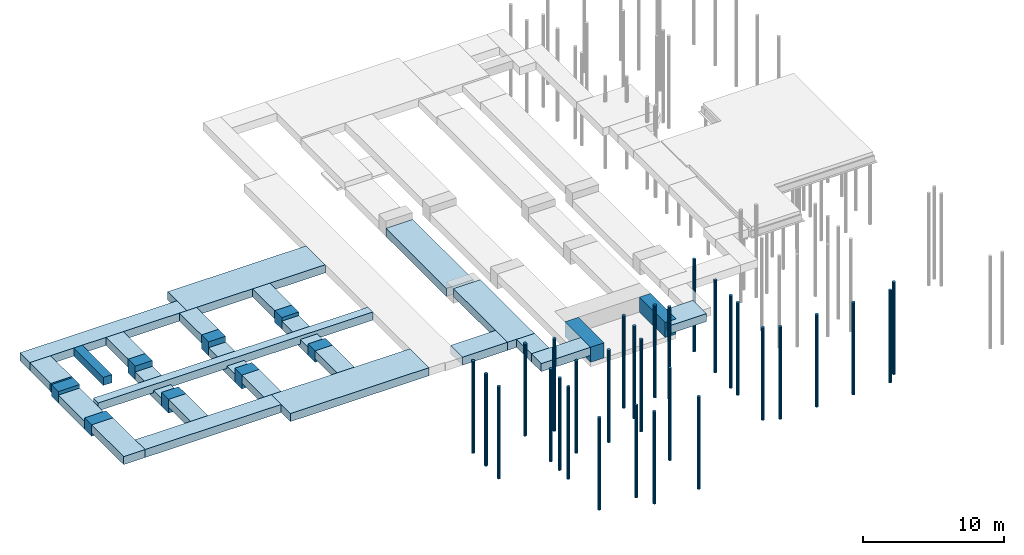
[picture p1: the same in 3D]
Properties of the parts of a building model (IFC4), part 31 of 45

# IfcWall (2385)
Name | In | Material | Faktor | Označení | Požární odolnost | Allright_Stavebni_dil_ID | Jednotka | Název_objektu | Object Layer Attributes #1, Status | Object Layer Attributes #1, Práce | Object Layer Attributes #1, Materiál | Object Layer Attributes #1, Staticky nosná konstrukce | Object Layer Attributes #1, Allright_Stavebni_dil_ID | Object Layer Attributes #1, Jednotka | Object Layer Attributes #1, Název_objektu | ThermalTransmittance (W/K/m2) | Width (m) | GrossSideArea (m2) | NetSideArea (m2) | GrossVolume (m3) | Length (m) | NetVolume (m3) | GrossFootprintArea (m2) | Height (m)
YTONG 150 | Půdorys 1.NP | YTONG 150 0.15 m | 1 | YTONG 150 | EI 180 | 1452HWa0798447301 | m3 | Celá stěna | Stávající | Zednické práce | YTONG 150 |  | 1452Stě0798447302 | m2 | Stěna | 0.794 | 0.15 | 0.167 | 0.168 | 0.025 | 0.05 | 0.025 | 0.007 | 3.35 | Pset_WallCommon - AcousticRating: 41 dB
YTONG 150 | Půdorys 1.NP | YTONG 150 0.15 m | 1 | YTONG 150 | EI 180 | 1452HWa0798447497 | m3 | Celá stěna | Stávající | Zednické práce | YTONG 150 |  | 1452Stě0798447498 | m2 | Stěna | 0.794 | 0.15 | 8.392 | 8.392 | 1.259 | 2.505 | 1.259 | 0.376 | 3.35 | Pset_WallCommon - AcousticRating: 41 dB
YTONG 150 | Půdorys 1.NP | YTONG 150 0.15 m | 1 | YTONG 150 | EI 180 | 1452HWa0798447524 | m3 | Celá stěna | Stávající | Zednické práce | YTONG 150 |  | 1452Stě0798447525 | m2 | Stěna | 0.794 | 0.15 | 2.01 | 2.01 | 0.302 | 0.6 | 0.302 | 0.09 | 3.35 | Pset_WallCommon - AcousticRating: 41 dB
ZDIVO Z CDm | Půdorys 1.NP | ZDIVO Z CDm 0.125 m | 1 | ZDIVO Z CDm | A | 1452HWa0798448210 | m3 | Celá stěna | Stávající | Zednické práce | ZDIVO Z CDm | yes | 1452Stě0798448211 | m3 | Stěna | 0 | 0.125 | 2.178 | 2.178 | 0.272 | 0.65 | 0.272 | 0.081 | 3.35
ZDIVO Z CDm | Půdorys 1.NP | ZDIVO Z CDm 0.125 m | 1 | ZDIVO Z CDm | A | 1452HWa0798448217 | m3 | Celá stěna | Stávající | Zednické práce | ZDIVO Z CDm | yes | 1452Stě0798448218 | m3 | Stěna | 0 | 0.125 | 1.106 | 1.106 | 0.138 | 0.33 | 0.138 | 0.041 | 3.35
SANITARNI WC PRICKA | Půdorys 1.NP | SANITÁRNÍ WC PŘÍČKA 0.032 m | 1 | SANITARNI WC PRICKA |  | 1452HWa0798448232 | m3 | Celá stěna | Stávající | Suché stavební práce | SANITÁRNÍ WC PŘÍČKA |  | 1452Stě0798448233 | m2 | Stěna |  | 0.032 | 1.896 | 0.49 | 0.061 | 1.025 | 0.016 | 0.033 | 1.85
SANITARNI WC PRICKA | Půdorys 1.NP | SANITÁRNÍ WC PŘÍČKA 0.032 m | 1 | SANITARNI WC PRICKA |  | 1452HWa0798448243 | m3 | Celá stěna | Stávající | Suché stavební práce | SANITÁRNÍ WC PŘÍČKA |  | 1452Stě0798448244 | m2 | Stěna |  | 0.032 | 3.052 | 1.647 | 0.098 | 1.65 | 0.053 | 0.053 | 1.85
SANITARNI WC PRICKA | Půdorys 1.NP | SANITÁRNÍ WC PŘÍČKA 0.032 m | 1 | SANITARNI WC PRICKA |  | 1452HWa0798448258 | m3 | Celá stěna | Stávající | Suché stavební práce | SANITÁRNÍ WC PŘÍČKA |  | 1452Stě0798448259 | m2 | Stěna |  | 0.032 | 2.729 | 1.323 | 0.087 | 1.475 | 0.042 | 0.047 | 1.85
ZDIVO Z CDm | Půdorys 1.NP | ZDIVO Z CDm 0.125 m | 1 | ZDIVO Z CDm | A | 1452HWa1096101619 | m3 | Celá stěna | Stávající | Zednické práce | ZDIVO Z CDm | yes | 1452Stě1096101620 | m3 | Stěna | 0 | 0.125 | 7.873 | 7.873 | 0.984 | 2.35 | 0.984 | 0.294 | 3.35
ZDIVO Z CDm | Půdorys 1.NP | ZDIVO Z CDm 0.125 m | 1 | ZDIVO Z CDm | A | 1452HWa1096101631 | m3 | Celá stěna | Stávající | Zednické práce | ZDIVO Z CDm | yes | 1452Stě1096101632 | m3 | Stěna | 0 | 0.125 | 7.873 | 7.373 | 0.984 | 2.35 | 0.922 | 0.294 | 3.35
ZDIVO Z CDm | Půdorys 1.NP | ZDIVO Z CDm 0.125 m | 1 | ZDIVO Z CDm | A | 1452HWa1096101643 | m3 | Celá stěna | Stávající | Zednické práce | ZDIVO Z CDm | yes | 1452Stě1096101644 | m3 | Stěna | 0 | 0.125 | 7.789 | 7.789 | 0.974 | 2.325 | 0.974 | 0.291 | 3.35
ZDIVO Z CDm | Půdorys 1.NP | ZDIVO Z CDm 0.125 m | 1 | ZDIVO Z CDm | A | 1452HWa1096101709 | m3 | Celá stěna | Stávající | Zednické práce | ZDIVO Z CDm | yes | 1452Stě1096101710 | m3 | Stěna | 0 | 0.125 | 5.042 | 5.042 | 0.63 | 1.505 | 0.63 | 0.188 | 3.35
ZDIVO Z CDm | Půdorys 1.NP | ZDIVO Z CDm 0.125 m | 1 | ZDIVO Z CDm | A | 1452HWa1096101719 | m3 | Celá stěna | Stávající | Zednické práce | ZDIVO Z CDm | yes | 1452Stě1096101720 | m3 | Stěna | 0 | 0.125 | 1.089 | 1.089 | 0.136 | 0.325 | 0.136 | 0.041 | 3.35
ZDIVO Z CDm | Půdorys 1.NP | ZDIVO Z CDm 0.125 m |  | ZDIVO Z CDm | A | 1452HWa0798445560 | m3 | Celá stěna | Stávající | Zednické práce | ZDIVO Z CDm |  | 1452Stě0798445561 | m3 | Stěna | 0 | 0.125 | 1.572 | 1.573 | 0.197 | 0.425 | 0.197 | 0.053 | 3.7
ZDIVO Z CDm | Půdorys 1.NP | ZDIVO Z CDm 0.125 m | 1 | ZDIVO Z CDm | A | 1452HWa1096102255 | m3 | Celá stěna | Stávající | Zednické práce | ZDIVO Z CDm | yes | 1452Stě1096102256 | m3 | Stěna | 0 | 0.125 | 22.546 | 22.546 | 2.818 | 6.73 | 2.818 | 0.841 | 3.35
ZDIVO Z CDm | Půdorys 1.NP | ZDIVO Z CDm 0.125 m | 1 | ZDIVO Z CDm | A | 1452HWa1096102340 | m3 | Celá stěna | Stávající | Zednické práce | ZDIVO Z CDm | yes | 1452Stě1096102341 | m3 | Stěna | 0 | 0.125 | 4.271 | 4.271 | 0.534 | 1.275 | 0.534 | 0.159 | 3.35
ZDIVO Z CDm | Půdorys 1.NP | ZDIVO Z CDm 0.125 m | 1 | ZDIVO Z CDm | A | 1452HWa1096102359 | m3 | Celá stěna | Stávající | Zednické práce | ZDIVO Z CDm | yes | 1452Stě1096102360 | m3 | Stěna | 0 | 0.125 | 3.853 | 3.853 | 0.482 | 1.15 | 0.482 | 0.144 | 3.35
YTONG 150 | Půdorys 1.NP | YTONG 150 0.15 m | 1 | YTONG 150 | EI 180 | 1452HWa1096102480 | m3 | Celá stěna | Stávající | Zednické práce | YTONG 150 |  | 1452Stě1096102481 | m2 | Stěna | 0.794 | 0.15 | 14.757 | 12.737 | 2.214 | 4.405 | 1.911 | 0.661 | 3.35 | Pset_WallCommon - AcousticRating: 41 dB
YTONG 100 | Půdorys 1.NP | YTONG 100 0.1 m | 1 | YTONG 100 | EI 120 | 1452HWa1096102495 | m3 | Celá stěna | Stávající | Zednické práce | YTONG 100 |  | 1452Stě1096102496 | m2 | Stěna | 1.111 | 0.1 | 0.737 | 0.737 | 0.074 | 0.22 | 0.074 | 0.022 | 3.35 | Pset_WallCommon - AcousticRating: 37 dB
YTONG 150 | Půdorys 1.NP | YTONG 150 0.15 m | 1 | YTONG 150 | EI 180 | 1452HWa1096102507 | m3 | Celá stěna | Stávající | Zednické práce | YTONG 150 |  | 1452Stě1096102508 | m2 | Stěna | 0.794 | 0.15 | 20.87 | 18.851 | 3.131 | 6.23 | 2.828 | 0.934 | 3.35 | Pset_WallCommon - AcousticRating: 41 dB
ZDIVO Z CDm | Půdorys 1.NP | ZDIVO Z CDm 0.125 m | 1 | ZDIVO Z CDm | A | 1452HWa1096102702 | m3 | Celá stěna | Stávající | Zednické práce | ZDIVO Z CDm | yes | 1452Stě1096102703 | m3 | Stěna | 0 | 0.125 | 1.675 | 1.675 | 0.209 | 0.5 | 0.209 | 0.063 | 3.35
ZDIVO Z CDm | Půdorys 1.NP | ZDIVO Z CDm 0.125 m | 1 | ZDIVO Z CDm | A | 1452HWa1096102722 | m3 | Celá stěna | Stávající | Zednické práce | ZDIVO Z CDm | yes | 1452Stě1096102723 | m3 | Stěna | 0 | 0.125 | 1.675 | 1.675 | 0.209 | 0.5 | 0.209 | 0.063 | 3.35
ZDIVO Z CDm | Půdorys 1.NP | ZDIVO Z CDm 0.125 m | 1 | ZDIVO Z CDm | A | 1452HWa1096102732 | m3 | Celá stěna | Stávající | Zednické práce | ZDIVO Z CDm | yes | 1452Stě1096102733 | m3 | Stěna | 0 | 0.125 | 1.256 | 1.256 | 0.157 | 0.375 | 0.157 | 0.047 | 3.35
ZDIVO Z CDm | Půdorys 1.NP | ZDIVO Z CDm 0.125 m | 1 | ZDIVO Z CDm | A | 1452HWa1096102866 | m3 | Celá stěna | Stávající | Zednické práce | ZDIVO Z CDm | yes | 1452Stě1096102867 | m3 | Stěna | 0 | 0.125 | 1.34 | 1.34 | 0.168 | 0.4 | 0.168 | 0.05 | 3.35
ZDIVO Z CDm | Půdorys 1.NP | ZDIVO Z CDm 0.125 m | 1 | ZDIVO Z CDm | A | 1452HWa1096102880 | m3 | Celá stěna | Stávající | Zednické práce | ZDIVO Z CDm | yes | 1452Stě1096102881 | m3 | Stěna | 0 | 0.125 | 14.757 | 14.757 | 1.845 | 4.405 | 1.845 | 0.551 | 3.35
ZDIVO Z CDm | Půdorys 1.NP | ZDIVO Z CDm 0.125 m | 1 | ZDIVO Z CDm | A | 1452HWa1096102907 | m3 | Celá stěna | Stávající | Zednické práce | ZDIVO Z CDm | yes | 1452Stě1096102908 | m3 | Stěna | 0 | 0.125 | 0.57 | 0.57 | 0.071 | 0.17 | 0.071 | 0.021 | 3.35
ZDIVO Z CDm | Půdorys 1.NP | ZDIVO Z CDm 0.125 m | 1 | ZDIVO Z CDm | A | 1452HWa1096102914 | m3 | Celá stěna | Stávající | Zednické práce | ZDIVO Z CDm | yes | 1452Stě1096102915 | m3 | Stěna | 0 | 0.125 | 1.926 | 1.926 | 0.241 | 0.575 | 0.241 | 0.072 | 3.35
ZDIVO Z CDm | Půdorys 1.NP | ZDIVO Z CDm 0.125 m | 1 | ZDIVO Z CDm | A | 1452HWa1096102835 | m3 | Celá stěna | Stávající | Zednické práce | ZDIVO Z CDm | yes | 1452Stě1096102836 | m3 | Stěna | 0 | 0.125 | 5.444 | 5.444 | 0.68 | 1.625 | 0.68 | 0.203 | 3.35
ZDIVO Z CDm | Půdorys 1.NP | ZDIVO Z CDm 0.125 m | 1 | ZDIVO Z CDm | A | 1452HWa1096102842 | m3 | Celá stěna | Stávající | Zednické práce | ZDIVO Z CDm | yes | 1452Stě1096102843 | m3 | Stěna | 0 | 0.125 | 3.099 | 2.599 | 0.387 | 0.925 | 0.325 | 0.116 | 3.35
ZDIVO Z CDm | Půdorys 1.NP | ZDIVO Z CDm 0.125 m | 1 | ZDIVO Z CDm | A | 1452HWa1096102854 | m3 | Celá stěna | Stávající | Zednické práce | ZDIVO Z CDm | yes | 1452Stě1096102855 | m3 | Stěna | 0 | 0.125 | 5.025 | 5.025 | 0.628 | 1.5 | 0.628 | 0.188 | 3.35
YTONG 125 | Půdorys 1.NP | YTONG 125 0.125 m | 1 | YTONG 125 | EI 180 | 1452HWa1096102999 | m3 | Celá stěna | Stávající | Zednické práce | YTONG 125 |  | 1452Stě1096103000 | m2 | Stěna | 0.926 | 0.125 | 4.271 | 4.271 | 0.534 | 1.275 | 0.534 | 0.159 | 3.35 | Pset_WallCommon - AcousticRating: 39 dB
YTONG 125 | Půdorys 1.NP | YTONG 125 0.125 m | 1 | YTONG 125 | EI 180 | 1452HWa1096103014 | m3 | Celá stěna | Stávající | Zednické práce | YTONG 125 |  | 1452Stě1096103015 | m2 | Stěna | 0.926 | 0.125 | 4.271 | 4.271 | 0.534 | 1.275 | 0.534 | 0.159 | 3.35 | Pset_WallCommon - AcousticRating: 39 dB
ZDIVO Z CDm | Půdorys 1.NP | ZDIVO Z CDm 0.125 m | 1 | ZDIVO Z CDm | A | 1452HWa1096103258 | m3 | Celá stěna | Stávající | Zednické práce | ZDIVO Z CDm | yes | 1452Stě1096103259 | m3 | Stěna | 0 | 0.125 | 3.434 | 3.434 | 0.429 | 1.025 | 0.429 | 0.128 | 3.35
ZDIVO Z CDm | Půdorys 1.NP | ZDIVO Z CDm 0.125 m | 1 | ZDIVO Z CDm | A | 1452HWa1096103267 | m3 | Celá stěna | Stávající | Zednické práce | ZDIVO Z CDm | yes | 1452Stě1096103268 | m3 | Stěna | 0 | 0.125 | 1.34 | 1.34 | 0.168 | 0.4 | 0.168 | 0.05 | 3.35
ZDIVO Z CDm | Půdorys 1.NP | ZDIVO Z CDm 0.125 m | 1 | ZDIVO Z CDm | A | 1452HWa1096103279 | m3 | Celá stěna | Stávající | Zednické práce | ZDIVO Z CDm | yes | 1452Stě1096103280 | m3 | Stěna | 0 | 0.125 | 1.91 | 1.91 | 0.239 | 0.57 | 0.239 | 0.071 | 3.35
ZDIVO Z CDm | Půdorys 1.NP | ZDIVO Z CDm 0.125 m | 1 | ZDIVO Z CDm | A | 1452HWa1096103293 | m3 | Celá stěna | Stávající | Zednické práce | ZDIVO Z CDm | yes | 1452Stě1096103294 | m3 | Stěna | 0 | 0.125 | 1.089 | 1.089 | 0.136 | 0.325 | 0.136 | 0.041 | 3.35
ZDIVO Z CDm | Půdorys 1.NP | ZDIVO Z CDm 0.125 m | 1 | ZDIVO Z CDm | A | 1452HWa1096103303 | m3 | Celá stěna | Stávající | Zednické práce | ZDIVO Z CDm | yes | 1452Stě1096103304 | m3 | Stěna | 0 | 0.125 | 3.182 | 3.183 | 0.398 | 0.95 | 0.398 | 0.119 | 3.35
ZDIVO Z CDm | Půdorys 1.NP | ZDIVO Z CDm 0.125 m | 1 | ZDIVO Z CDm | A | 1452HWa1096103314 | m3 | Celá stěna | Stávající | Zednické práce | ZDIVO Z CDm | yes | 1452Stě1096103315 | m3 | Stěna | 0 | 0.125 | 1.089 | 1.089 | 0.136 | 0.325 | 0.136 | 0.041 | 3.35
YTONG 150 | Půdorys 1.NP | YTONG 150 0.15 m | 1 | YTONG 150 | EI 180 | 1452HWa1096103378 | m3 | Celá stěna | Stávající | Zednické práce | YTONG 150 |  | 1452Stě1096103379 | m2 | Stěna | 0.794 | 0.15 | 11.742 | 11.742 | 1.761 | 3.505 | 1.761 | 0.526 | 3.35 | Pset_WallCommon - AcousticRating: 41 dB
YTONG 150 | Půdorys 1.NP | YTONG 150 0.15 m | 1 | YTONG 150 | EI 180 | 1452HWa1096103390 | m3 | Celá stěna | Stávající | Zednické práce | YTONG 150 |  | 1452Stě1096103391 | m2 | Stěna | 0.794 | 0.15 | 4.522 | 4.523 | 0.678 | 1.35 | 0.678 | 0.202 | 3.35 | Pset_WallCommon - AcousticRating: 41 dB
YTONG 100 | Půdorys 1.NP | YTONG 100 0.1 m | 1 | YTONG 100 | EI 120 | 1452HWa1096103402 | m3 | Celá stěna | Stávající | Zednické práce | YTONG 100 |  | 1452Stě1096103403 | m2 | Stěna | 1.111 | 0.1 | 1.675 | 1.675 | 0.167 | 0.5 | 0.167 | 0.05 | 3.35 | Pset_WallCommon - AcousticRating: 37 dB
YTONG 100 | Půdorys 1.NP | YTONG 100 0.1 m | 1 | YTONG 100 | EI 120 | 1452HWa1096103419 | m3 | Celá stěna | Stávající | Zednické práce | YTONG 100 |  | 1452Stě1096103420 | m2 | Stěna | 1.111 | 0.1 | 0.921 | 0.921 | 0.092 | 0.275 | 0.092 | 0.028 | 3.35 | Pset_WallCommon - AcousticRating: 37 dB
YTONG 150 | Půdorys 1.NP | YTONG 150 0.15 m | 1 | YTONG 150 | EI 180 | 1452HWa1096103435 | m3 | Celá stěna | Stávající | Zednické práce | YTONG 150 |  | 1452Stě1096103436 | m2 | Stěna | 0.794 | 0.15 | 21.122 | 19.102 | 3.168 | 6.305 | 2.865 | 0.946 | 3.35 | Pset_WallCommon - AcousticRating: 41 dB
ZDIVO Z CDm | Půdorys 1.NP | ZDIVO Z CDm 0.125 m | 1 | ZDIVO Z CDm | A | 1452HWa1096103544 | m3 | Celá stěna | Stávající | Zednické práce | ZDIVO Z CDm | yes | 1452Stě1096103545 | m3 | Stěna | 0 | 0.125 | 1.005 | 1.005 | 0.126 | 0.3 | 0.126 | 0.037 | 3.35
YTONG | Půdorys 1.NP | YTONG 0.275 m | 1 | YTONG | EI 180 | 1452HWa1096103618 | m3 | Celá stěna | Stávající | Zednické práce | YTONG |  | 1452Stě1096103619 | m2 | Stěna | 0.794 | 0.275 | 1.424 | 1.424 | 0.392 | 0.425 | 0.392 | 0.117 | 3.35 | Pset_WallCommon - AcousticRating: 41 dB
ZDIVO Z CDm | Půdorys 1.NP | ZDIVO Z CDm 0.125 m | 1 | ZDIVO Z CDm | A | 1452HWa1096103522 | m3 | Celá stěna | Stávající | Zednické práce | ZDIVO Z CDm | yes | 1452Stě1096103523 | m3 | Stěna | 0 | 0.125 | 1.424 | 1.424 | 0.178 | 0.425 | 0.178 | 0.053 | 3.35
ZDIVO Z CDm | Půdorys 1.NP | ZDIVO Z CDm 0.125 m | 1 | ZDIVO Z CDm | A | 1452HWa1096103532 | m3 | Celá stěna | Stávající | Zednické práce | ZDIVO Z CDm | yes | 1452Stě1096103533 | m3 | Stěna | 0 | 0.125 | 3.099 | 3.099 | 0.387 | 0.925 | 0.387 | 0.116 | 3.35
ZDIVO Z CDm | Půdorys 1.NP | ZDIVO Z CDm 0.125 m | 1 | ZDIVO Z CDm | A | 1452HWa1096103802 | m3 | Celá stěna | Stávající | Zednické práce | ZDIVO Z CDm | yes | 1452Stě1096103803 | m3 | Stěna | 0 | 0.125 | 5.611 | 5.611 | 0.701 | 1.675 | 0.701 | 0.209 | 3.35
ZDIVO Z CDm | Půdorys 1.NP | ZDIVO Z CDm 0.125 m | 1 | ZDIVO Z CDm | A | 1452HWa1096103809 | m3 | Celá stěna | Stávající | Zednické práce | ZDIVO Z CDm | yes | 1452Stě1096103810 | m3 | Stěna | 0 | 0.125 | 4.271 | 4.271 | 0.534 | 1.275 | 0.534 | 0.159 | 3.35
ZDIVO Z CDm | Půdorys 1.NP | ZDIVO Z CDm 0.125 m | 1 | ZDIVO Z CDm | A | 1452HWa1096103816 | m3 | Celá stěna | Stávající | Zednické práce | ZDIVO Z CDm | yes | 1452Stě1096103817 | m3 | Stěna | 0 | 0.125 | 4.271 | 4.271 | 0.534 | 1.275 | 0.534 | 0.159 | 3.35
ZDIVO Z CDm | Půdorys 1.NP | ZDIVO Z CDm 0.125 m | 1 | ZDIVO Z CDm | A | 1452HWa1096103828 | m3 | Celá stěna | Stávající | Zednické práce | ZDIVO Z CDm | yes | 1452Stě1096103829 | m3 | Stěna | 0 | 0.125 | 19.413 | 17.393 | 2.427 | 5.795 | 2.174 | 0.724 | 3.35
ZDIVO Z CDm | Půdorys 1.NP | ZDIVO Z CDm 0.125 m | 1 | ZDIVO Z CDm | A | 1452HWa1096103850 | m3 | Celá stěna | Stávající | Zednické práce | ZDIVO Z CDm | yes | 1452Stě1096103851 | m3 | Stěna | 0 | 0.125 | 1.524 | 1.524 | 0.191 | 0.455 | 0.191 | 0.057 | 3.35
ZDIVO Z CDm | Půdorys 1.NP | ZDIVO Z CDm 0.125 m | 1 | ZDIVO Z CDm | A | 1452HWa1096103859 | m3 | Celá stěna | Stávající | Zednické práce | ZDIVO Z CDm | yes | 1452Stě1096103860 | m3 | Stěna | 0 | 0.125 | 5.192 | 5.193 | 0.649 | 1.55 | 0.649 | 0.194 | 3.35
ZDIVO Z CDm | Půdorys 1.NP | ZDIVO Z CDm 0.125 m | 1 | ZDIVO Z CDm | A | 1452HWa1096103876 | m3 | Celá stěna | Stávající | Zednické práce | ZDIVO Z CDm | yes | 1452Stě1096103877 | m3 | Stěna | 0 | 0.125 | 1.005 | 1.005 | 0.126 | 0.3 | 0.126 | 0.038 | 3.35
ZDIVO Z CDm | Půdorys 1.NP | ZDIVO Z CDm 0.125 m | 1 | ZDIVO Z CDm | A | 1452HWa1096103888 | m3 | Celá stěna | Stávající | Zednické práce | ZDIVO Z CDm | yes | 1452Stě1096103889 | m3 | Stěna | 0 | 0.125 | 1.005 | 1.005 | 0.126 | 0.3 | 0.126 | 0.038 | 3.35
PÓROBETONOVÉ ZDIVO | Půdorys 1.NP | PÓROBETONOVÉ ZDIVO 0.25 m | 1 | PÓROBETONOVÉ ZDIVO | REI 180 | 1452HWa1096103943 | m3 | Celá stěna | Stávající | Zednické práce | PÓROBETONOVÉ ZDIVO |  | 1452Stě1096103944 | m3 | Stěna | 0.541 | 0.25 | 1.26 | 1.26 | 0.315 | 0.35 | 0.315 | 0.088 | 3.6 | Pset_WallCommon - AcousticRating: 48 dB
PÓROBETONOVÉ ZDIVO | Půdorys 1.NP | PÓROBETONOVÉ ZDIVO 0.12 m | 1 | PÓROBETONOVÉ ZDIVO | EI 120 | 1452HWa1096104017 | m3 | Celá stěna | Stávající | Zednické práce | PÓROBETONOVÉ ZDIVO |  | 1452Stě1096104018 | m2 | Stěna | 1.111 | 0.12 | 17.336 | 17.336 | 2.08 | 5.175 | 2.08 | 0.621 | 3.35 | Pset_WallCommon - AcousticRating: 37 dB
ZDIVO Z CDm | Půdorys 1.NP | ZDIVO Z CDm 0.125 m | 1 | ZDIVO Z CDm | A | 1452HWa1096104109 | m3 | Celá stěna | Stávající | Zednické práce | ZDIVO Z CDm | yes | 1452Stě1096104110 | m3 | Stěna | 0 | 0.125 | 5.611 | 5.611 | 0.701 | 1.675 | 0.701 | 0.209 | 3.35
YTONG 150 | Půdorys 1.NP | YTONG 150 0.15 m | 1 | YTONG 150 | EI 180 | 1452HWa0798447743 | m3 | Celá stěna | Stávající | Zednické práce | YTONG 150 |  | 1452Stě0798447744 | m2 | Stěna | 0.794 | 0.15 | 17.567 | 11.507 | 2.635 | 5.244 | 1.726 | 0.787 | 3.35 | Pset_WallCommon - AcousticRating: 41 dB
ZDIVO Z CDm | Půdorys 1.NP | ZDIVO Z CDm 0.125 m | 1 | ZDIVO Z CDm | A | 1452HWa1096102373 | m3 | Celá stěna | Stávající | Zednické práce | ZDIVO Z CDm | yes | 1452Stě1096102374 | m3 | Stěna | 0 | 0.125 | 5.611 | 5.611 | 0.701 | 1.675 | 0.701 | 0.209 | 3.35
YTONG 125 | Půdorys 1.NP | YTONG 125 0.125 m | 1 | YTONG 125 | EI 180 | 1452HWa1096104393 | m3 | Celá stěna | Stávající | Zednické práce | YTONG 125 | no | 1452Stě1096104402 | m2 | Stěna | 0.926 | 0.125 | 9.966 | 9.966 | 1.246 | 2.975 | 1.246 | 0.372 | 3.35 | Pset_WallCommon - AcousticRating: 39 dB
ZDIVO Z CDm | Půdorys 1.NP | ZDIVO Z CDm 0.2 m | 1 | ZDIVO Z CDm | A | 1452HWa1096104394 | m3 | Celá stěna | Stávající | Zednické práce | ZDIVO Z CDm | no | 1452Stě1096104399 | m3 | Stěna | 0 | 0.2 | 2.01 | 2.01 | 0.402 | 0.6 | 0.402 | 0.12 | 3.35
ZDIVO Z CDm | Půdorys 1.NP | ZDIVO Z CDm 0.125 m | 1 | ZDIVO Z CDm | A | 1452HWa1096104396 | m3 | Celá stěna | Stávající | Zednické práce | ZDIVO Z CDm |  | 1452Stě1096104404 | m3 | Stěna | 0 | 0.125 | 20.201 | 20.573 | 2.525 | 6.03 | 2.521 | 0.754 | 3.35
ZDIVO Z CDm | Půdorys 1.NP | ZDIVO Z CDm 0.125 m | 1 | ZDIVO Z CDm | A | 1452HWa1096102347 | m3 | Celá stěna | Stávající | Zednické práce | ZDIVO Z CDm | yes | 1452Stě1096102348 | m3 | Stěna | 0 | 0.125 | 1.759 | 1.359 | 0.22 | 0.525 | 0.17 | 0.066 | 3.35
ZDIVO Z CDm | Půdorys 1.NP | ZDIVO Z CDm 0.125 m |  | ZDIVO Z CDm | A | 1452HWa0000001483 | m3 | Celá stěna | Stávající | Zednické práce | ZDIVO Z CDm | no | 1452Stě0000001503 | m3 | Stěna | 0 | 0.125 | 8.64 | 8.64 | 1.08 | 2.4 | 1.08 | 0.3 | 3.6
ZDIVO Z CDm | Půdorys 1.NP | ZDIVO Z CDm 0.125 m | 1 | ZDIVO Z CDm | A | 1452HWa1096104894 | m3 | Celá stěna | Stávající | Zednické práce | ZDIVO Z CDm | yes | 1452Stě1096104895 | m3 | Stěna | 0 | 0.125 | 1.34 | 1.34 | 0.167 | 0.4 | 0.167 | 0.05 | 3.35
ZDIVO Z CDm | Půdorys 1.NP | ZDIVO Z CDm 0.125 m | 1 | ZDIVO Z CDm | A | 1452HWa1096104904 | m3 | Celá stěna | Stávající | Zednické práce | ZDIVO Z CDm | yes | 1452Stě1096104905 | m3 | Stěna | 0 | 0.125 | 0.754 | 0.754 | 0.094 | 0.225 | 0.094 | 0.028 | 3.35
ZDIVO Z CDm | Půdorys 1.NP | ZDIVO Z CDm 0.125 m | 1 | ZDIVO Z CDm | A | 1452HWa1096104173 | m3 | Celá stěna | Stávající | Zednické práce | ZDIVO Z CDm | yes | 1452Stě1096104174 | m3 | Stěna | 0 | 0.125 | 6.03 | 6.03 | 0.754 | 1.8 | 0.754 | 0.225 | 3.35
ZDIVO Z CDm | Půdorys 1.NP | EPS 0.1 m, ZDIVO Z CDm 0.5 m |  | ZDIVO Z CDm | A | 1452HWa0000000002 | m3 | Celá stěna | Stávající | Zateplovací systémy | EPS |  | 1452Stě0000001497 | m2 | Stěna | 0 | 0.6 | 31.135 | 31.136 | 17.1 | 8.85 | 17.1 | 5.11 | 3.35 | NEMSOK - Object Layer Attributes #2, 2D interakce: yes; Object Layer Attributes #2, Status: Stávající; Object Layer Attributes #2, Práce: Zednické práce; Object Layer Attributes #2, Materiál: ZDIVO Z CDm; Object Layer Attributes #2, Allright_Stavebni_dil_ID: 1452Stě1096104937; Object Layer Attributes #2, Jednotka: m3; Object Layer Attributes #2, Název_objektu: Stěna
ZDIVO Z CDm | Půdorys 1.NP | EPS 0.1 m, ZDIVO Z CDm 0.5 m | 1 | ZDIVO Z CDm | A | 1452HWa0000000004 | m3 | Celá stěna | Stávající | Zateplovací systémy | EPS |  | 1452Stě0000001507 | m2 | Stěna | 0 | 0.6 | 11.655 | 11.655 | 6.023 | 3.2 | 6.023 | 1.8 | 3.35 | NEMSOK - Object Layer Attributes #2, 2D interakce: yes; Object Layer Attributes #2, Status: Stávající; Object Layer Attributes #2, Práce: Zednické práce; Object Layer Attributes #2, Materiál: ZDIVO Z CDm; Object Layer Attributes #2, Allright_Stavebni_dil_ID: 1452Stě1096105225; Object Layer Attributes #2, Jednotka: m3; Object Layer Attributes #2, Název_objektu: Stěna
ZDIVO Z CDm | Půdorys 1.NP | EPS 0.1 m, ZDIVO Z CDm 0.5 m | 1 | ZDIVO Z CDm | A | 1452HWa0000000006 | m3 | Celá stěna | Stávající | Zateplovací systémy | EPS |  | 1452Stě0000001493 | m2 | Stěna | 0 | 0.6 | 23.785 | 23.785 | 14.257 | 7.1 | 14.257 | 4.26 | 3.35 | NEMSOK - Object Layer Attributes #2, 2D interakce: yes; Object Layer Attributes #2, Status: Stávající; Object Layer Attributes #2, Práce: Zednické práce; Object Layer Attributes #2, Materiál: ZDIVO Z CDm; Object Layer Attributes #2, Allright_Stavebni_dil_ID: 1452Stě1096105291; Object Layer Attributes #2, Jednotka: m3; Object Layer Attributes #2, Název_objektu: Stěna
ZDIVO Z CDm | Půdorys 1.NP | ZDIVO Z CDm 0.5 m | 1 | ZDIVO Z CDm | A | 1452HWa1096105649 | m3 | Celá stěna | Stávající | Zednické práce | ZDIVO Z CDm | yes | 1452Stě1096105655 | m3 | Stěna | 0 | 0.5 | 16.582 | 11.201 | 8.291 | 4.95 | 5.6 | 2.475 | 3.35
ZDIVO Z CDm | Půdorys 1.NP | EPS | 1 | ZDIVO Z CDm | A | 1452HWa0000001485 | m3 | Celá stěna | Stávající | Zateplovací systémy | EPS |  | 1452Stě0000001488 | m2 | Stěna | 0 | 0.6 | 28.804 | 23.418 | 17.202 | 8.6 | 13.994 | 5.14 | 3.35 | NEMSOK - Object Layer Attributes #2, 2D interakce: yes; Object Layer Attributes #2, Status: Stávající; Object Layer Attributes #2, Práce: Zednické práce; Object Layer Attributes #2, Materiál: ZDIVO Z CDm; Object Layer Attributes #2, Allright_Stavebni_dil_ID: 1452Stě1096105427; Object Layer Attributes #2, Jednotka: m3; Object Layer Attributes #2, Název_objektu: Stěna
ZDIVO Z CDm | Půdorys 1.NP | EPS 0.1 m, ZDIVO Z CDm 0.5 m | 1 | ZDIVO Z CDm | A | 1452HWa0000000016 | m3 | Celá stěna | Stávající | Zateplovací systémy | EPS |  | 1452Stě0000001501 | m2 | Stěna | 0 | 0.6 | 2.68 | 2.68 | 1.606 | 0.8 | 1.606 | 0.48 | 3.35 | NEMSOK - Object Layer Attributes #2, 2D interakce: yes; Object Layer Attributes #2, Status: Stávající; Object Layer Attributes #2, Práce: Zednické práce; Object Layer Attributes #2, Materiál: ZDIVO Z CDm; Object Layer Attributes #2, Allright_Stavebni_dil_ID: 1452Stě1096105687; Object Layer Attributes #2, Jednotka: m3; Object Layer Attributes #2, Název_objektu: Stěna
ZDIVO Z CDm | Půdorys 1.NP | ZDIVO Z CDm 0.22 m |  | ZDIVO Z CDm | A | 1452HWa1096106019 | m3 | Celá stěna | Stávající | Zednické práce | ZDIVO Z CDm |  | 1452Stě1096106024 | m3 | Stěna | 0 | 0.22 | 4.439 | 4.439 | 0.977 | 1.325 | 0.799 | 0.292 | 3.35
ZDIVO Z CDm | Půdorys 1.NP | ZDIVO Z CDm 0.125 m | 1 | ZDIVO Z CDm | A | 1452HWa1096106021 | m3 | Celá stěna | Stávající | Zednické práce | ZDIVO Z CDm |  | 1452Stě1096106026 | m3 | Stěna | 0 | 0.125 | 1.005 | 1.005 | 0.126 | 0.3 | 0.126 | 0.037 | 3.35
ZDIVO Z CDm | Půdorys 1.NP | ZDIVO Z CDm 0.125 m | 1 | ZDIVO Z CDm | A | 1452HWa0798431186 | m3 | Celá stěna | Stávající | Zednické práce | ZDIVO Z CDm |  | 1452Stě0798431187 | m3 | Stěna | 0 | 0.125 | 1.507 | 1.508 | 0.188 | 0.45 | 0.188 | 0.056 | 3.35
ZDIVO Z CDm | Půdorys 1.NP | ZDIVO Z CDm 0.125 m | 1 | ZDIVO Z CDm | A | 1452HWa1096107384 | m3 | Celá stěna | Stávající | Zednické práce | ZDIVO Z CDm |  | 1452Stě1096107386 | m3 | Stěna | 0 | 0.125 | 1.089 | 1.089 | 0.136 | 0.325 | 0.136 | 0.041 | 3.35
ZDIVO Z CDm | Půdorys 1.NP | ZDIVO Z CDm 0.125 m | 1 | ZDIVO Z CDm | A | 1452HWa1096107389 | m3 | Celá stěna | Stávající | Zednické práce | ZDIVO Z CDm |  | 1452Stě1096107390 | m3 | Stěna | 0 | 0.125 | 0.67 | 0.67 | 0.084 | 0.2 | 0.084 | 0.025 | 3.35
STÁVAJÍCÍ KCE | Půdorys 1.NP | STÁVAJÍC KCE 0.4 m | 1 | STÁVAJÍCÍ KCE | REI 180 | 1452HWa1096107553 | m3 | Celá stěna | Stávající | Zednické práce | STÁVAJÍC KCE | yes | 1452Stě1096107554 | m3 | Stěna | 0.541 | 0.4 | 1.926 | 2.011 | 0.771 | 0.575 | 0.771 | 0.23 | 3.35 | Pset_WallCommon - AcousticRating: 48 dB
STÁVAJÍCÍ KCE | Půdorys 1.NP | STÁVAJÍC KCE 0.1 m | 1 | STÁVAJÍCÍ KCE | REI 180 | 1452HWa1096107576 | m3 | Celá stěna | Stávající | Zednické práce | STÁVAJÍC KCE | yes | 1452Stě1096107577 | m3 | Stěna | 0.541 | 0.1 | 0.502 | 0.503 | 0.05 | 0.15 | 0.05 | 0.015 | 3.35 | Pset_WallCommon - AcousticRating: 48 dB
STÁVAJÍCÍ KCE | Půdorys 1.NP | STÁVAJÍC KCE 0.1 m | 1 | STÁVAJÍCÍ KCE | REI 180 | 1452HWa1096107586 | m3 | Celá stěna | Stávající | Zednické práce | STÁVAJÍC KCE | yes | 1452Stě1096107587 | m3 | Stěna | 0.541 | 0.1 | 0.502 | 0.503 | 0.05 | 0.15 | 0.05 | 0.015 | 3.35 | Pset_WallCommon - AcousticRating: 48 dB
STÁVAJÍCÍ KCE | Půdorys 1.NP | STÁVAJÍC KCE 0.1 m | 1 | STÁVAJÍCÍ KCE | REI 180 | 1452HWa1096107634 | m3 | Celá stěna | Stávající | Zednické práce | STÁVAJÍC KCE | yes | 1452Stě1096107635 | m3 | Stěna | 0.541 | 0.1 | 0.502 | 0.503 | 0.05 | 0.15 | 0.05 | 0.015 | 3.35 | Pset_WallCommon - AcousticRating: 48 dB
STÁVAJÍCÍ KCE | Půdorys 1.NP | STÁVAJÍC KCE 0.1 m | 1 | STÁVAJÍCÍ KCE | REI 180 | 1452HWa1096107644 | m3 | Celá stěna | Stávající | Zednické práce | STÁVAJÍC KCE | yes | 1452Stě1096107645 | m3 | Stěna | 0.541 | 0.1 | 0.502 | 0.503 | 0.05 | 0.15 | 0.05 | 0.015 | 3.35 | Pset_WallCommon - AcousticRating: 48 dB
STÁVAJÍCÍ KCE | Půdorys 1.NP | STÁVAJÍC KCE 0.1 m | 1 | STÁVAJÍCÍ KCE | REI 180 | 1452HWa1096107654 | m3 | Celá stěna | Stávající | Zednické práce | STÁVAJÍC KCE | yes | 1452Stě1096107655 | m3 | Stěna | 0.541 | 0.1 | 0.502 | 0.503 | 0.05 | 0.15 | 0.05 | 0.015 | 3.35 | Pset_WallCommon - AcousticRating: 48 dB
STÁVAJÍCÍ KCE | Půdorys 1.NP | STÁVAJÍC KCE 0.1 m | 1 | STÁVAJÍCÍ KCE | REI 180 | 1452HWa1096107664 | m3 | Celá stěna | Stávající | Zednické práce | STÁVAJÍC KCE | yes | 1452Stě1096107665 | m3 | Stěna | 0.541 | 0.1 | 0.502 | 0.503 | 0.05 | 0.15 | 0.05 | 0.015 | 3.35 | Pset_WallCommon - AcousticRating: 48 dB
ZDIVO Z CDm | Půdorys 1.NP | ZDIVO Z CDm 0.125 m | 1 | ZDIVO Z CDm | A | 1452HWa0798422835 | m3 | Celá stěna | Stávající | Zednické práce | ZDIVO Z CDm | yes | 1452Stě0798422836 | m3 | Stěna | 0 | 0.125 | 10.72 | 10.72 | 1.34 | 3.2 | 1.34 | 0.4 | 3.35
ZDIVO Z CDm | Půdorys 1.NP | ZDIVO Z CDm 0.125 m | 1 | ZDIVO Z CDm | A | 1452HWa0798431170 | m3 | Celá stěna | Stávající | Zednické práce | ZDIVO Z CDm |  | 1452Stě0798431171 | m3 | Stěna | 0 | 0.125 | 15.41 | 15.41 | 1.926 | 4.6 | 1.926 | 0.575 | 3.35
ZDIVO Z CDm | Půdorys 1.NP | ZDIVO Z CDm 0.125 m | 1 | ZDIVO Z CDm | A | 1452HWa0798431160 | m3 | Celá stěna | Stávající | Zednické práce | ZDIVO Z CDm |  | 1452Stě0798431161 | m3 | Stěna | 0 | 0.125 | 2.429 | 2.429 | 0.304 | 0.725 | 0.304 | 0.091 | 3.35
ZDIVO Z CDm | Půdorys 1.NP | ZDIVO Z CDm 0.125 m | 1 | ZDIVO Z CDm | A | 1452HWa0798431035 | m3 | Celá stěna | Stávající | Zednické práce | ZDIVO Z CDm | yes | 1452Stě0798431036 | m3 | Stěna | 0 | 0.125 | 0.335 | 0.335 | 0.042 | 0.1 | 0.042 | 0.012 | 3.35
ZDIVO Z CDm | Půdorys 1.NP | ZDIVO Z CDm 0.125 m | 1 | ZDIVO Z CDm | A | 1452HWa0798431276 | m3 | Celá stěna | Stávající | Zednické práce | ZDIVO Z CDm | yes | 1452Stě0798431277 | m3 | Stěna | 0 | 0.125 | 10.552 | 10.553 | 1.319 | 3.15 | 1.319 | 0.394 | 3.35
ZDIVO Z CDm | Půdorys 1.NP | ZDIVO Z CDm 0.125 m | 1 | ZDIVO Z CDm | A | 1452HWa0798432641 | m3 | Celá stěna | Stávající | Zednické práce | ZDIVO Z CDm | yes | 1452Stě0798432642 | m3 | Stěna | 0 | 0.125 | 3.35 | 3.35 | 0.419 | 1 | 0.419 | 0.125 | 3.35
ZDIVO Z CDm | Půdorys 1.NP | ZDIVO Z CDm 0.125 m | 1 | ZDIVO Z CDm | A | 1452HWa0798431534 | m3 | Celá stěna | Stávající | Zednické práce | ZDIVO Z CDm | yes | 1452Stě0798431535 | m3 | Stěna | 0 | 0.125 | 11.223 | 11.223 | 1.403 | 3.35 | 1.403 | 0.419 | 3.35
ZDIVO Z CDm | Půdorys 1.NP | ZDIVO Z CDm 0.125 m | 1 | ZDIVO Z CDm | A | 1452HWa0798441101 | m3 | Celá stěna | Stávající | Zednické práce | ZDIVO Z CDm | yes | 1452Stě0798441102 | m3 | Stěna | 0 | 0.125 | 9.631 | 8.015 | 1.204 | 2.875 | 1.002 | 0.359 | 3.35
ZDIVO Z CDm | Půdorys 1.NP | ZDIVO Z CDm 0.125 m | 1 | ZDIVO Z CDm | A | 1452HWa0798441111 | m3 | Celá stěna | Stávající | Zednické práce | ZDIVO Z CDm | yes | 1452Stě0798441112 | m3 | Stěna | 0 | 0.125 | 2.01 | 2.01 | 0.251 | 0.6 | 0.251 | 0.075 | 3.35
ZDIVO Z CDm | Půdorys 1.NP | ZDIVO Z CDm 0.125 m | 1 | ZDIVO Z CDm | A | 1452HWa0798441118 | m3 | Celá stěna | Stávající | Zednické práce | ZDIVO Z CDm | yes | 1452Stě0798441119 | m3 | Stěna | 0 | 0.125 | 1.591 | 1.591 | 0.199 | 0.475 | 0.199 | 0.059 | 3.35
ZDIVO Z CDm | Půdorys 1.NP | ZDIVO Z CDm 0.125 m | 1 | ZDIVO Z CDm | A | 1452HWa0798426451 | m3 | Celá stěna | Stávající | Zednické práce | ZDIVO Z CDm | yes | 1452Stě0798426452 | m3 | Stěna | 0 | 0.125 | 44.22 | 37.62 | 5.528 | 13.2 | 4.703 | 1.65 | 3.35
ZDIVO Z CDm | Půdorys 1.NP | ZDIVO Z CDm 0.125 m | 1 | ZDIVO Z CDm | A | 1452HWa0798431783 | m3 | Celá stěna | Stávající | Zednické práce | ZDIVO Z CDm | yes | 1452Stě0798431784 | m3 | Stěna | 0 | 0.125 | 6.851 | 6.817 | 0.856 | 2.045 | 0.852 | 0.256 | 3.35
ZDIVO Z CDm | Půdorys 1.NP | ZDIVO Z CDm 0.125 m | 1 | ZDIVO Z CDm | A | 1452HWa0798431776 | m3 | Celá stěna | Stávající | Zednické práce | ZDIVO Z CDm | yes | 1452Stě0798431777 | m3 | Stěna | 0 | 0.125 | 10.05 | 6.6 | 1.256 | 3 | 0.825 | 0.375 | 3.35
ZDIVO Z CDm | Půdorys 1.NP | ZDIVO Z CDm 0.125 m | 1 | ZDIVO Z CDm | A | 1452HWa0798431793 | m3 | Celá stěna | Stávající | Zednické práce | ZDIVO Z CDm | yes | 1452Stě0798431794 | m3 | Stěna | 0 | 0.125 | 1.591 | 1.397 | 0.199 | 0.475 | 0.175 | 0.059 | 3.35
ZDIVO Z CDm | Půdorys 1.NP | ZDIVO Z CDm 0.125 m | 1 | ZDIVO Z CDm | A | 1452HWa0798442037 | m3 | Celá stěna | Stávající | Zednické práce | ZDIVO Z CDm | yes | 1452Stě0798442038 | m3 | Stěna | 0 | 0.125 | 9.045 | 3.795 | 1.131 | 2.7 | 0.474 | 0.338 | 3.35
ZDIVO Z CDm | Půdorys 1.NP | ZDIVO Z CDm 0.125 m | 1 | ZDIVO Z CDm | A | 1452HWa1096110475 | m3 | Celá stěna | Stávající | Zednické práce | ZDIVO Z CDm | yes | 1452Stě1096110476 | m3 | Stěna | 0 | 0.125 | 4.774 | 3.36 | 0.597 | 1.425 | 0.42 | 0.178 | 3.35
ZDIVO Z CDm | Půdorys 1.NP | ZDIVO Z CDm 0.125 m | 1 | ZDIVO Z CDm | A | 1452HWa1096110480 | m3 | Celá stěna | Stávající | Zednické práce | ZDIVO Z CDm | yes | 1452Stě1096110481 | m3 | Stěna | 0 | 0.125 | 16.038 | 14.624 | 2.005 | 4.787 | 1.828 | 0.598 | 3.35
ZDIVO Z CDm | Půdorys 1.NP | ZDIVO Z CDm 0.125 m | 1 | ZDIVO Z CDm | A | 1452HWa1096110519 | m3 | Celá stěna | Stávající | Zednické práce | ZDIVO Z CDm | yes | 1452Stě1096110520 | m3 | Stěna | 0 | 0.125 | 3.517 | 3.518 | 0.44 | 1.05 | 0.44 | 0.131 | 3.35
ZDIVO Z CDm | Půdorys 1.NP | ZDIVO Z CDm 0.125 m | 1 | ZDIVO Z CDm | A | 1452HWa1096110490 | m3 | Celá stěna | Stávající | Zednické práce | ZDIVO Z CDm | yes | 1452Stě1096110491 | m3 | Stěna | 0 | 0.125 | 3.015 | 3.015 | 0.377 | 0.9 | 0.377 | 0.113 | 3.35
ZDIVO Z CDm | Půdorys 1.NP | ZDIVO Z CDm 0.25 m | 1 | ZDIVO Z CDm | A | 1452HWa1096110502 | m3 | Celá stěna | Stávající | Zednické práce | ZDIVO Z CDm | yes | 1452Stě1096110503 | m3 | Stěna | 0 | 0.25 | 14.698 | 14.698 | 3.675 | 4.388 | 3.675 | 1.097 | 3.35
STÁVAJÍCÍ KCE | Půdorys 1.NP | STÁVAJÍC KCE 0.4 m |  | STÁVAJÍCÍ KCE | REI 180 | 1452HWa0798429829 | m3 | Celá stěna | Stávající | Zednické práce | STÁVAJÍC KCE | yes | 1452Stě0798429831 | m3 | Stěna | 0.541 | 0.4 | 8.878 | 9.045 | 3.551 | 2.65 | 3.551 | 1.06 | 3.35 | Pset_WallCommon - AcousticRating: 48 dB
STÁVAJÍCÍ KCE | Půdorys 1.NP | STÁVAJÍC KCE 0.4 m | 1 | STÁVAJÍCÍ KCE | REI 180 | 1452HWa0798429923 | m3 | Celá stěna | Stávající | Zednické práce | STÁVAJÍC KCE | yes | 1452Stě0798429924 | m3 | Stěna | 0.541 | 0.4 | 31.49 | 16.595 | 12.596 | 9.4 | 6.638 | 3.76 | 3.35 | Pset_WallCommon - AcousticRating: 48 dB
STÁVAJÍCÍ KCE | Půdorys 1.NP | STÁVAJÍC KCE 0.1 m | 1 | STÁVAJÍCÍ KCE | REI 180 | 1452HWa1096107610 | m3 | Celá stěna | Stávající | Zednické práce | STÁVAJÍC KCE | yes | 1452Stě1096107611 | m3 | Stěna | 0.541 | 0.1 | 0.502 | 0.503 | 0.05 | 0.15 | 0.05 | 0.015 | 3.35 | Pset_WallCommon - AcousticRating: 48 dB
STÁVAJÍCÍ KCE | Půdorys 1.NP | STÁVAJÍC KCE 0.1 m | 1 | STÁVAJÍCÍ KCE | REI 180 | 1452HWa1096107623 | m3 | Celá stěna | Stávající | Zednické práce | STÁVAJÍC KCE | yes | 1452Stě1096107624 | m3 | Stěna | 0.541 | 0.1 | 0.502 | 0.503 | 0.05 | 0.15 | 0.05 | 0.015 | 3.35 | Pset_WallCommon - AcousticRating: 48 dB
ZDIVO Z CDm | Půdorys 1.NP | ZDIVO Z CDm 0.125 m | 1 | ZDIVO Z CDm | A | 1452HWa0798431711 | m3 | Celá stěna | Stávající | Zednické práce | ZDIVO Z CDm | yes | 1452Stě0798431712 | m3 | Stěna | 0 | 0.125 | 3.082 | 3.082 | 0.385 | 0.92 | 0.385 | 0.115 | 3.35
PÓROBETONOVÉ ZDIVO | Půdorys 1.NP | PÓROBETONOVÉ ZDIVO 0.12 m | 1 | PÓROBETONOVÉ ZDIVO | EI 120 | 1452HWa1096112136 | m3 | Celá stěna | Stávající | Zednické práce | PÓROBETONOVÉ ZDIVO | no | 1452Stě1096112137 | m2 | Stěna | 1.111 | 0.12 | 16.248 | 16.183 | 1.95 | 4.85 | 1.942 | 0.582 | 3.35 | Pset_WallCommon - AcousticRating: 37 dB
YTONG 125 | Půdorys 1.NP | YTONG 125 0.125 m | 1 | YTONG 125 | EI 180 | 1452HWa1096112790 | m3 | Celá stěna | Stávající | Zednické práce | YTONG 125 | no | 1452Stě1096112792 | m2 | Stěna | 0.926 | 0.125 | 12.162 | 12.163 | 1.52 | 3.475 | 1.52 | 0.434 | 3.5 | Pset_WallCommon - AcousticRating: 39 dB
YTONG 150 | Půdorys 1.NP | YTONG 150 | 1 | YTONG 150 | EI 180 | 1452HWa1096112824 | m3 | Celá stěna | Stávající | Zednické práce | YTONG 150 |  | 1452Stě1096112825 | m2 | Stěna | 0.794 | 0.15 | 6.929 | 6.929 | 1.039 | 2.068 | 1.039 | 0.31 | 3.35 | Pset_WallCommon - AcousticRating: 41 dB
YTONG 150 | Půdorys 1.NP | YTONG 150 0.15 m | 1 | YTONG 150 | EI 180 | 1452HWa1096112852 | m3 | Celá stěna | Stávající | Zednické práce | YTONG 150 |  | 1452Stě1096112853 | m2 | Stěna | 0.794 | 0.15 | 0.378 | 0.378 | 0.057 | 0.113 | 0.057 | 0.017 | 3.35 | Pset_WallCommon - AcousticRating: 41 dB
YTONG 150 | Půdorys 1.NP | YTONG 150 0.15 m | 1 | YTONG 150 | EI 180 | 1452HWa1096112866 | m3 | Celá stěna | Stávající | Zednické práce | YTONG 150 |  | 1452Stě1096112867 | m2 | Stěna | 0.794 | 0.15 | 0.378 | 0.378 | 0.057 | 0.113 | 0.057 | 0.017 | 3.35 | Pset_WallCommon - AcousticRating: 41 dB
YTONG 125 | Půdorys 1.NP | YTONG 125 0.125 m | 1 | YTONG 125 | EI 180 | 1452HWa1096112879 | m3 | Celá stěna | Stávající | Zednické práce | YTONG 125 | no | 1452Stě1096112880 | m2 | Stěna | 0.926 | 0.125 | 10.412 | 10.413 | 1.302 | 2.975 | 1.302 | 0.372 | 3.5 | Pset_WallCommon - AcousticRating: 39 dB
ZDIVO Z CDm | Půdorys 1.NP | ZDIVO Z CDm 0.125 m | 1 | ZDIVO Z CDm | A | 1452HWa1096113157 | m3 | Celá stěna | Stávající | Zednické práce | ZDIVO Z CDm |  | 1452Stě1096113158 | m3 | Stěna | 0 | 0.125 | 22.378 | 22.378 | 2.797 | 6.68 | 2.797 | 0.835 | 3.35
ZDIVO Z CDm | Půdorys 1.NP | ZDIVO Z CDm 0.125 m | 1 | ZDIVO Z CDm | A | 1452HWa1096113167 | m3 | Celá stěna | Stávající | Zednické práce | ZDIVO Z CDm |  | 1452Stě1096113168 | m3 | Stěna | 0 | 0.125 | 46.816 | 39.044 | 5.852 | 13.975 | 4.881 | 1.747 | 3.35
ZDIVO Z CDm | Půdorys 1.NP | ZDIVO Z CDm 0.125 m | 1 | ZDIVO Z CDm | A | 1452HWa1096113174 | m3 | Celá stěna | Stávající | Zednické práce | ZDIVO Z CDm |  | 1452Stě1096113175 | m3 | Stěna | 0 | 0.125 | 5.276 | 5.276 | 0.66 | 1.575 | 0.66 | 0.197 | 3.35
ZDIVO Z CDm | Půdorys 1.NP | ZDIVO Z CDm 0.125 m | 1 | ZDIVO Z CDm | A | 1452HWa1096113198 | m3 | Celá stěna | Stávající | Zednické práce | ZDIVO Z CDm |  | 1452Stě1096113199 | m3 | Stěna | 0 | 0.125 | 2.01 | 2.01 | 0.251 | 0.6 | 0.251 | 0.075 | 3.35
ZDIVO Z CDm | Půdorys 1.NP | ZDIVO Z CDm 0.125 m | 1 | ZDIVO Z CDm | A | 1452HWa1096113212 | m3 | Celá stěna | Stávající | Zednické práce | ZDIVO Z CDm |  | 1452Stě1096113213 | m3 | Stěna | 0 | 0.125 | 1.34 | 1.34 | 0.168 | 0.4 | 0.168 | 0.05 | 3.35
ZDIVO Z CDm | Půdorys 1.NP | ZDIVO Z CDm 0.125 m | 1 | ZDIVO Z CDm | A | 1452HWa1096113224 | m3 | Celá stěna | Stávající | Zednické práce | ZDIVO Z CDm |  | 1452Stě1096113225 | m3 | Stěna | 0 | 0.125 | 2.01 | 2.01 | 0.251 | 0.6 | 0.251 | 0.075 | 3.35
ZDIVO Z CDm | Půdorys 1.NP | ZDIVO Z CDm 0.125 m | 1 | ZDIVO Z CDm | A | 1452HWa1096113235 | m3 | Celá stěna | Stávající | Zednické práce | ZDIVO Z CDm |  | 1452Stě1096113236 | m3 | Stěna | 0 | 0.125 | 2.429 | 2.429 | 0.304 | 0.725 | 0.304 | 0.091 | 3.35
ZDIVO Z CDm | Půdorys 1.NP | ZDIVO Z CDm 0.125 m | 1 | ZDIVO Z CDm | A | 1452HWa1096113249 | m3 | Celá stěna | Stávající | Zednické práce | ZDIVO Z CDm |  | 1452Stě1096113250 | m3 | Stěna | 0 | 0.125 | 3.015 | 3.015 | 0.377 | 0.9 | 0.377 | 0.112 | 3.35
ZDIVO Z CDm | Půdorys 1.NP | ZDIVO Z CDm 0.125 m | 1 | ZDIVO Z CDm | A | 1452HWa1096113274 | m3 | Celá stěna | Stávající | Zednické práce | ZDIVO Z CDm |  | 1452Stě1096113275 | m3 | Stěna | 0 | 0.125 | 1.926 | 1.926 | 0.241 | 0.575 | 0.241 | 0.072 | 3.35
YTONG 125 | Půdorys 1.NP | YTONG 125 0.125 m | 1 | YTONG 125 | EI 180 | 1452HWa1096113310 | m3 | Celá stěna | Stávající | Zednické práce | YTONG 125 | no | 1452Stě1096113311 | m2 | Stěna | 0.926 | 0.125 | 11.223 | 11.223 | 1.403 | 3.206 | 1.403 | 0.401 | 3.5 | Pset_WallCommon - AcousticRating: 39 dB
YTONG 100 | Půdorys 1.NP | YTONG 100 0.1 m | 1 | YTONG 100 | EI 120 | 1452HWa1096113499 | m3 | Celá stěna | Stávající | Zednické práce | YTONG 100 |  | 1452Stě1096113500 | m2 | Stěna | 1.111 | 0.1 | 1.508 | 1.508 | 0.151 | 0.45 | 0.151 | 0.045 | 3.35 | Pset_WallCommon - AcousticRating: 37 dB
ZDIVO Z CDm | Půdorys 1.NP | ZDIVO Z CDm 0.125 m | 1 | ZDIVO Z CDm | A | 1452HWa1096113530 | m3 | Celá stěna | Stávající | Zednické práce | ZDIVO Z CDm |  | 1452Stě1096113531 | m3 | Stěna | 0 | 0.125 | 2.429 | 2.429 | 0.304 | 0.725 | 0.304 | 0.091 | 3.35
ZDIVO Z CDm | Půdorys 1.NP | ZDIVO Z CDm 0.125 m | 1 | ZDIVO Z CDm | A | 1452HWa1096113540 | m3 | Celá stěna | Stávající | Zednické práce | ZDIVO Z CDm |  | 1452Stě1096113541 | m3 | Stěna | 0 | 0.125 | 2.68 | 2.68 | 0.335 | 0.8 | 0.335 | 0.1 | 3.35
ZDIVO Z CDm | Půdorys 1.NP | ZDIVO Z CDm 0.125 m | 1 | ZDIVO Z CDm | A | 1452HWa1096113554 | m3 | Celá stěna | Stávající | Zednické práce | ZDIVO Z CDm |  | 1452Stě1096113555 | m3 | Stěna | 0 | 0.125 | 1.507 | 1.508 | 0.188 | 0.45 | 0.188 | 0.056 | 3.35
ZDIVO Z CDm | Půdorys 1.NP | ZDIVO Z CDm 0.125 m | 1 | ZDIVO Z CDm | A | 1452HWa1096113565 | m3 | Celá stěna | Stávající | Zednické práce | ZDIVO Z CDm |  | 1452Stě1096113566 | m3 | Stěna | 0 | 0.125 | 2.01 | 2.01 | 0.251 | 0.6 | 0.251 | 0.075 | 3.35
ZDIVO Z CDm | Půdorys 1.NP | ZDIVO Z CDm 0.125 m | 1 | ZDIVO Z CDm | A | 1452HWa0798432511 | m3 | Celá stěna | Stávající | Zednické práce | ZDIVO Z CDm | yes | 1452Stě0798432512 | m3 | Stěna | 0 | 0.125 | 22.11 | 18.878 | 2.764 | 6.6 | 2.36 | 0.825 | 3.35
YTONG 100 | Půdorys 1.NP | YTONG 100 0.1 m | 1 | YTONG 100 | EI 120 | 1452HWa0798432712 | m3 | Celá stěna | Stávající | Zednické práce | YTONG 100 |  | 1452Stě0798432713 | m2 | Stěna | 1.111 | 0.1 | 6.951 | 6.951 | 0.695 | 2.075 | 0.695 | 0.208 | 3.35 | Pset_WallCommon - AcousticRating: 37 dB
YTONG 100 | Půdorys 1.NP | YTONG 100 0.1 m | 1 | YTONG 100 | EI 120 | 1452HWa0798432735 | m3 | Celá stěna | Stávající | Zednické práce | YTONG 100 |  | 1452Stě0798432736 | m2 | Stěna | 1.111 | 0.1 | 6.951 | 3.719 | 0.695 | 2.075 | 0.372 | 0.208 | 3.35 | Pset_WallCommon - AcousticRating: 37 dB
ZDIVO Z CDm | Půdorys 1.NP | ZDIVO Z CDm 0.125 m | 1 | ZDIVO Z CDm | A | 1452HWa0798432605 | m3 | Celá stěna | Stávající | Zednické práce | ZDIVO Z CDm | yes | 1452Stě0798432606 | m3 | Stěna | 0 | 0.125 | 3.769 | 3.769 | 0.471 | 1.125 | 0.471 | 0.141 | 3.35
ZDIVO Z CDm | Půdorys 1.NP | ZDIVO Z CDm 0.125 m | 1 | ZDIVO Z CDm | A | 1452HWa0798432625 | m3 | Celá stěna | Stávající | Zednické práce | ZDIVO Z CDm | yes | 1452Stě0798432626 | m3 | Stěna | 0 | 0.125 | 12.06 | 12.06 | 1.507 | 3.6 | 1.507 | 0.45 | 3.35
ZDIVO Z CDm | Půdorys 1.NP | ZDIVO Z CDm 0.125 m | 1 | ZDIVO Z CDm | A | 1452HWa0798432835 | m3 | Celá stěna | Stávající | Zednické práce | ZDIVO Z CDm | yes | 1452Stě0798432836 | m3 | Stěna | 0 | 0.125 | 14.237 | 10.804 | 1.78 | 4.25 | 1.35 | 0.531 | 3.35
ZDIVO Z CDm | Půdorys 1.NP | ZDIVO Z CDm 0.125 m | 1 | ZDIVO Z CDm | A | 1452HWa0798432775 | m3 | Celá stěna | Stávající | Zednické práce | ZDIVO Z CDm | yes | 1452Stě0798432776 | m3 | Stěna | 0 | 0.125 | 6.951 | 6.951 | 0.869 | 2.075 | 0.869 | 0.259 | 3.35
YTONG 100 | Půdorys 1.NP | YTONG 100 0.1 m | 1 | YTONG 100 | EI 120 | 1452HWa1096113941 | m3 | Celá stěna | Stávající | Zednické práce | YTONG 100 |  | 1452Stě1096113942 | m2 | Stěna | 1.111 | 0.1 | 9.631 | 8.015 | 0.963 | 2.875 | 0.802 | 0.287 | 3.35 | Pset_WallCommon - AcousticRating: 37 dB
YTONG 100 | Půdorys 1.NP | YTONG 100 0.1 m | 1 | YTONG 100 | EI 120 | 1452HWa1096113964 | m3 | Celá stěna | Stávající | Zednické práce | YTONG 100 |  | 1452Stě1096113965 | m2 | Stěna | 1.111 | 0.1 | 4.02 | 4.02 | 0.402 | 1.2 | 0.402 | 0.12 | 3.35 | Pset_WallCommon - AcousticRating: 37 dB
YTONG 100 | Půdorys 1.NP | YTONG 100 0.1 m | 1 | YTONG 100 | EI 120 | 1452HWa0798432532 | m3 | Celá stěna | Stávající | Zednické práce | YTONG 100 |  | 1452Stě0798432533 | m2 | Stěna | 1.111 | 0.1 | 6.449 | 4.833 | 0.645 | 1.925 | 0.483 | 0.193 | 3.35 | Pset_WallCommon - AcousticRating: 37 dB
ZDIVO Z CDm | Půdorys 1.NP | ZDIVO Z CDm 0.125 m | 1 | ZDIVO Z CDm | A | 1452HWa1096114334 | m3 | Celá stěna | Stávající | Zednické práce | ZDIVO Z CDm |  | 1452Stě1096114335 | m3 | Stěna | 0 | 0.125 | 2.847 | 2.848 | 0.356 | 0.85 | 0.356 | 0.106 | 3.35
YTONG 100 | Půdorys 1.NP | YTONG 100 0.1 m | 1 | YTONG 100 | EI 120 | 1452HWa1096114384 | m3 | Celá stěna | Stávající | Zednické práce | YTONG 100 |  | 1452Stě1096114385 | m2 | Stěna | 1.111 | 0.1 | 2.261 | 2.261 | 0.226 | 0.675 | 0.226 | 0.068 | 3.35 | Pset_WallCommon - AcousticRating: 37 dB
YTONG 100 | Půdorys 1.NP | YTONG 100 0.1 m | 1 | YTONG 100 | EI 120 | 1452HWa1096114399 | m3 | Celá stěna | Stávající | Zednické práce | YTONG 100 |  | 1452Stě1096114400 | m2 | Stěna | 1.111 | 0.1 | 2.261 | 2.261 | 0.226 | 0.675 | 0.226 | 0.068 | 3.35 | Pset_WallCommon - AcousticRating: 37 dB
ZDIVO Z CDm | Půdorys 1.NP | ZDIVO Z CDm 0.125 m | 1 | ZDIVO Z CDm | A | 1452HWa1096114519 | m3 | Celá stěna | Stávající | Zednické práce | ZDIVO Z CDm | yes | 1452Stě1096114520 | m3 | Stěna | 0 | 0.125 | 0.335 | 0.335 | 0.042 | 0.1 | 0.042 | 0.012 | 3.35
ZDIVO Z CDm | Půdorys 1.NP | ZDIVO Z CDm 0.125 m | 1 | ZDIVO Z CDm | A | 1452HWa0798431253 | m3 | Celá stěna | Stávající | Zednické práce | ZDIVO Z CDm | yes | 1452Stě0798431254 | m3 | Stěna | 0 | 0.125 | 2.01 | 2.01 | 0.251 | 0.6 | 0.251 | 0.075 | 3.35
ZDIVO Z CDm | Půdorys 1.NP | ZDIVO Z CDm 0.125 m | 1 | ZDIVO Z CDm | A | 1452HWa0798431263 | m3 | Celá stěna | Stávající | Zednické práce | ZDIVO Z CDm | yes | 1452Stě0798431264 | m3 | Stěna | 0 | 0.125 | 3.283 | 3.283 | 0.41 | 0.98 | 0.41 | 0.123 | 3.35
ZDIVO Z CDm | Půdorys 1.NP | ZDIVO Z CDm 0.125 m | 1 | ZDIVO Z CDm | A | 1452HWa1096114803 | m3 | Celá stěna | Stávající | Zednické práce | ZDIVO Z CDm |  | 1452Stě1096114804 | m3 | Stěna | 0 | 0.125 | 0.67 | 0.67 | 0.084 | 0.2 | 0.084 | 0.025 | 3.35
ZDIVO Z CDm | Půdorys 1.NP | ZDIVO Z CDm 0.125 m | 1 | ZDIVO Z CDm | A | 1452HWa1096114902 | m3 | Celá stěna | Stávající | Zednické práce | ZDIVO Z CDm | yes | 1452Stě1096114903 | m3 | Stěna | 0 | 0.125 | 8.71 | 8.71 | 1.089 | 2.6 | 1.089 | 0.325 | 3.35
ZDIVO Z CDm | Půdorys 1.NP | ZDIVO Z CDm 0.125 m | 1 | ZDIVO Z CDm | A | 1452HWa1096114825 | m3 | Celá stěna | Stávající | Zednické práce | ZDIVO Z CDm |  | 1452Stě1096114826 | m3 | Stěna | 0 | 0.125 | 4.606 | 4.606 | 0.576 | 1.375 | 0.576 | 0.172 | 3.35
ZDIVO Z CDm | Půdorys 1.NP | ZDIVO Z CDm 0.125 m | 1 | ZDIVO Z CDm | A | 1452HWa1096115245 | m3 | Celá stěna | Stávající | Zednické práce | ZDIVO Z CDm | yes | 1452Stě1096115265 | m3 | Stěna | 0 | 0.125 | 9.631 | 8.015 | 1.204 | 2.875 | 1.002 | 0.359 | 3.35
ZDIVO Z CDm | Půdorys 1.NP | ZDIVO Z CDm 0.125 m | 1 | ZDIVO Z CDm | A | 1452HWa0798432542 | m3 | Celá stěna | Stávající | Zednické práce | ZDIVO Z CDm | yes | 1452Stě0798432543 | m3 | Stěna | 0 | 0.125 | 10.988 | 10.72 | 1.374 | 3.28 | 1.374 | 0.41 | 3.35
ZDIVO Z CDm | Půdorys 1.NP | ZDIVO Z CDm 0.125 m | 1 | ZDIVO Z CDm | A | 1452HWa0798433460 | m3 | Celá stěna | Stávající | Zednické práce | ZDIVO Z CDm | yes | 1452Stě0798433513 | m3 | Stěna | 0 | 0.125 | 5.863 | 3.843 | 0.733 | 1.75 | 0.48 | 0.219 | 3.35
ZDIVO Z CDm | Půdorys 1.NP | ZDIVO Z CDm 0.125 m | 1 | ZDIVO Z CDm | A | 1452HWa0798433425 | m3 | Celá stěna | Stávající | Zednické práce | ZDIVO Z CDm | yes | 1452Stě0798433426 | m3 | Stěna | 0 | 0.125 | 1.089 | 1.089 | 0.136 | 0.325 | 0.136 | 0.041 | 3.35
ZDIVO Z CDm | Půdorys 1.NP | ZDIVO Z CDm 0.125 m | 1 | ZDIVO Z CDm | A | 1452HWa0798433435 | m3 | Celá stěna | Stávající | Zednické práce | ZDIVO Z CDm | yes | 1452Stě0798433436 | m3 | Stěna | 0 | 0.125 | 2.01 | 2.01 | 0.251 | 0.6 | 0.251 | 0.075 | 3.35
ZDIVO Z CDm | Půdorys 1.NP | ZDIVO Z CDm 0.125 m | 1 | ZDIVO Z CDm | A | 1452HWa0798431048 | m3 | Celá stěna | Stávající | Zednické práce | ZDIVO Z CDm | yes | 1452Stě0798431049 | m3 | Stěna | 0 | 0.125 | 0.335 | 0.335 | 0.042 | 0.1 | 0.042 | 0.013 | 3.35
ZDIVO Z CDm | Půdorys 1.NP | ZDIVO Z CDm 0.125 m | 1 | ZDIVO Z CDm | A | 1452HWa1096116179 | m3 | Celá stěna | Stávající | Zednické práce | ZDIVO Z CDm |  | 1452Stě1096116180 | m3 | Stěna | 0 | 0.125 | 18.844 | 13.496 | 2.355 | 5.625 | 1.687 | 0.703 | 3.35
ZDIVO Z CDm | Půdorys 1.NP | ZDIVO Z CDm 0.125 m | 1 | ZDIVO Z CDm | A | 1452HWa1096116195 | m3 | Celá stěna | Stávající | Zednické práce | ZDIVO Z CDm |  | 1452Stě1096116196 | m3 | Stěna | 0 | 0.125 | 3.015 | 3.015 | 0.377 | 0.9 | 0.377 | 0.113 | 3.35
PÓROBETONOVÉ ZDIVO | Půdorys 1.NP | PÓROBETONOVÉ ZDIVO 0.12 m | 1 | PÓROBETONOVÉ ZDIVO | EI 120 | 1452HWa1096116376 | m3 | Celá stěna | Stávající | Zednické práce | PÓROBETONOVÉ ZDIVO | no | 1452Stě1096116377 | m2 | Stěna | 1.111 | 0.12 | 50.016 | 40.341 | 6.002 | 14.93 | 4.841 | 1.792 | 3.35 | Pset_WallCommon - AcousticRating: 37 dB
ZDIVO Z CDm | Půdorys 1.NP | ZDIVO Z CDm 0.125 m | 1 | ZDIVO Z CDm | A | 1452HWa1096116361 | m3 | Celá stěna | Stávající | Zednické práce | ZDIVO Z CDm |  | 1452Stě1096116362 | m3 | Stěna | 0 | 0.125 | 0.771 | 0.771 | 0.096 | 0.23 | 0.096 | 0.029 | 3.35
ZDIVO Z CDm | Půdorys 1.NP | ZDIVO Z CDm 0.125 m | 1 | ZDIVO Z CDm | A | 1452HWa1096116346 | m3 | Celá stěna | Stávající | Zednické práce | ZDIVO Z CDm |  | 1452Stě1096116347 | m3 | Stěna | 0 | 0.125 | 0.771 | 0.771 | 0.096 | 0.23 | 0.096 | 0.029 | 3.35
ZDIVO Z CDm | Půdorys 1.NP | ZDIVO Z CDm 0.2 m | 1 | ZDIVO Z CDm | A | 1452HWa1096116605 | m3 | Celá stěna | Stávající | Zednické práce | ZDIVO Z CDm | no | 1452Stě1096116606 | m3 | Stěna | 0 | 0.2 | 2.781 | 2.781 | 0.556 | 0.83 | 0.556 | 0.166 | 3.35
ZDIVO Z CDm | Půdorys 1.NP | ZDIVO Z CDm 0.2 m | 1 | ZDIVO Z CDm | A | 1452HWa1096116689 | m3 | Celá stěna | Stávající | Zednické práce | ZDIVO Z CDm | no | 1452Stě1096116691 | m3 | Stěna | 0 | 0.2 | 2.01 | 2.01 | 0.402 | 0.6 | 0.402 | 0.12 | 3.35
ZDIVO Z CDm | Půdorys 1.NP | ZDIVO Z CDm 0.125 m | 1 | ZDIVO Z CDm | A | 1452HWa1096116162 | m3 | Celá stěna | Stávající | Zednické práce | ZDIVO Z CDm |  | 1452Stě1096116163 | m3 | Stěna | 0 | 0.125 | 3.015 | 3.015 | 0.377 | 0.9 | 0.377 | 0.113 | 3.35
ZDIVO Z CDm | Půdorys 1.NP | ZDIVO Z CDm 0.125 m | 1 | ZDIVO Z CDm | A | 1452HWa1096116713 | m3 | Celá stěna | Stávající | Zednické práce | ZDIVO Z CDm |  | 1452Stě1096116717 | m3 | Stěna | 0 | 0.125 | 10.05 | 10.05 | 1.256 | 3 | 1.256 | 0.375 | 3.35
YTONG 100 | Půdorys 1.NP | YTONG 100 0.1 m | 1 | YTONG 100 | EI 120 | 1452HWa1096116771 | m3 | Celá stěna | Stávající | Zednické práce | YTONG 100 |  | 1452Stě1096116772 | m2 | Stěna | 1.111 | 0.1 | 1.675 | 1.675 | 0.168 | 0.5 | 0.168 | 0.05 | 3.35 | Pset_WallCommon - AcousticRating: 37 dB
ZDIVO Z CDm | Půdorys 1.NP | ZDIVO Z CDm 0.125 m | 1 | ZDIVO Z CDm | A | 1452HWa1096116778 | m3 | Celá stěna | Stávající | Zednické práce | ZDIVO Z CDm |  | 1452Stě1096116779 | m3 | Stěna | 0 | 0.125 | 1.842 | 1.843 | 0.23 | 0.55 | 0.23 | 0.069 | 3.35
ZDIVO Z CDm | Půdorys 1.NP | ZDIVO Z CDm 0.125 m | 1 | ZDIVO Z CDm | A | 1452HWa1096116800 | m3 | Celá stěna | Stávající | Zednické práce | ZDIVO Z CDm |  | 1452Stě1096116801 | m3 | Stěna | 0 | 0.125 | 2.261 | 2.261 | 0.283 | 0.675 | 0.283 | 0.084 | 3.35
ZDIVO Z CDm | Půdorys 1.NP | ZDIVO Z CDm 0.125 m | 1 | ZDIVO Z CDm | A | 1452HWa1096116810 | m3 | Celá stěna | Stávající | Zednické práce | ZDIVO Z CDm |  | 1452Stě1096116811 | m3 | Stěna | 0 | 0.125 | 3.685 | 3.685 | 0.461 | 1.1 | 0.461 | 0.138 | 3.35
ZDIVO Z CDm | Půdorys 1.NP | ZDIVO Z CDm 0.125 m | 1 | ZDIVO Z CDm | A | 1452HWa1096116824 | m3 | Celá stěna | Stávající | Zednické práce | ZDIVO Z CDm |  | 1452Stě1096116825 | m3 | Stěna | 0 | 0.125 | 1.507 | 1.508 | 0.188 | 0.45 | 0.188 | 0.056 | 3.35
ZDIVO Z CDm | Půdorys 1.NP | ZDIVO Z CDm 0.125 m |  | ZDIVO Z CDm | A | 1452HWa0798432904 | m3 | Celá stěna | Stávající | Zednické práce | ZDIVO Z CDm | yes | 1452Stě0798432905 | m3 | Stěna | 0 | 0.125 | 5.695 | 5.695 | 0.712 | 1.7 | 0.712 | 0.213 | 3.35
ZDIVO Z CDm | Půdorys 1.NP | ZDIVO Z CDm 0.125 m | 1 | ZDIVO Z CDm | A | 1452HWa0798432993 | m3 | Celá stěna | Stávající | Zednické práce | ZDIVO Z CDm | yes | 1452Stě0798432994 | m3 | Stěna | 0 | 0.125 | 0.335 | 0.335 | 0.042 | 0.1 | 0.042 | 0.012 | 3.35
ZDIVO Z CDm | Půdorys 1.NP | ZDIVO Z CDm 0.125 m | 1 | ZDIVO Z CDm | A | 1452HWa0798433005 | m3 | Celá stěna | Stávající | Zednické práce | ZDIVO Z CDm | yes | 1452Stě0798433006 | m3 | Stěna | 0 | 0.125 | 0.335 | 0.335 | 0.042 | 0.1 | 0.042 | 0.013 | 3.35
ZDIVO Z CDm | Půdorys 1.NP | ZDIVO Z CDm 0.125 m | 1 | ZDIVO Z CDm | A | 1452HWa0798433017 | m3 | Celá stěna | Stávající | Zednické práce | ZDIVO Z CDm | yes | 1452Stě0798433019 | m3 | Stěna | 0 | 0.125 | 5.276 | 4.776 | 0.66 | 1.575 | 0.597 | 0.197 | 3.35
ZDIVO Z CDm | Půdorys 1.NP | ZDIVO Z CDm 0.125 m | 1 | ZDIVO Z CDm | A | 1452HWa0798432915 | m3 | Celá stěna | Stávající | Zednické práce | ZDIVO Z CDm | yes | 1452Stě0798432916 | m3 | Stěna | 0 | 0.125 | 2.094 | 2.094 | 0.262 | 0.625 | 0.262 | 0.078 | 3.35
ZDIVO Z CDm | Půdorys 1.NP | ZDIVO Z CDm 0.125 m | 1 | ZDIVO Z CDm | A | 1452HWa0798431198 | m3 | Celá stěna | Stávající | Zednické práce | ZDIVO Z CDm |  | 1452Stě0798431199 | m3 | Stěna | 0 | 0.125 | 17.856 | 17.856 | 2.232 | 5.33 | 2.232 | 0.666 | 3.35
ZDIVO Z CDm | Půdorys 1.NP | ZDIVO Z CDm 0.25 m | 1 | ZDIVO Z CDm | A | 1452HWa1096117240 | m3 | Celá stěna | Stávající | Zednické práce | ZDIVO Z CDm |  | 1452Stě1096117242 | m3 | Stěna | 0 | 0.25 | 12.831 | 12.831 | 3.208 | 3.83 | 3.208 | 0.958 | 3.35
ZDIVO Z CDm | Půdorys 1.NP | ZDIVO Z CDm 0.125 m | 1 | ZDIVO Z CDm | A | 1452HWa1096117312 | m3 | Celá stěna | Stávající | Zednické práce | ZDIVO Z CDm |  | 1452Stě1096117313 | m3 | Stěna | 0 | 0.125 | 1.507 | 1.508 | 0.188 | 0.45 | 0.188 | 0.056 | 3.35
YTONG 125 | Půdorys 1.NP | YTONG 125 0.125 m | 1 | YTONG 125 | EI 180 | 1452HWa1096117324 | m3 | Celá stěna | Stávající | Zednické práce | YTONG 125 |  | 1452Stě1096117325 | m2 | Stěna | 0.926 | 0.125 | 19.267 | 16.518 | 2.408 | 5.505 | 2.065 | 0.688 | 3.5 | Pset_WallCommon - AcousticRating: 39 dB
YTONG 125 | Půdorys 1.NP | YTONG 125 0.125 m | 1 | YTONG 125 | EI 180 | 1452HWa1096117336 | m3 | Celá stěna | Stávající | Zednické práce | YTONG 125 |  | 1452Stě1096117337 | m2 | Stěna | 0.926 | 0.125 | 18.9 | 17.284 | 2.363 | 5.4 | 2.161 | 0.675 | 3.5 | Pset_WallCommon - AcousticRating: 39 dB
YTONG 125 | Půdorys 1.NP | YTONG 125 0.125 m | 1 | YTONG 125 | EI 180 | 1452HWa1096117346 | m3 | Celá stěna | Stávající | Zednické práce | YTONG 125 |  | 1452Stě1096117347 | m2 | Stěna | 0.926 | 0.125 | 3.063 | 1.447 | 0.383 | 0.875 | 0.181 | 0.109 | 3.5 | Pset_WallCommon - AcousticRating: 39 dB
ZDIVO Z CDm | Půdorys 1.NP | ZDIVO Z CDm 0.125 m | 1 | ZDIVO Z CDm | A | 1452HWa1096116790 | m3 | Celá stěna | Stávající | Zednické práce | ZDIVO Z CDm |  | 1452Stě1096116791 | m3 | Stěna | 0 | 0.125 | 6.449 | 6.449 | 0.806 | 1.925 | 0.806 | 0.241 | 3.35
ZDIVO Z CDm | Půdorys 1.NP | ZDIVO Z CDm 0.125 m | 1 | ZDIVO Z CDm | A | 1452HWa1096117386 | m3 | Celá stěna | Stávající | Zednické práce | ZDIVO Z CDm |  | 1452Stě1096117387 | m3 | Stěna | 0 | 0.125 | 0.168 | 0.168 | 0.021 | 0.05 | 0.021 | 0.006 | 3.35
ZDIVO Z CDm | Půdorys 1.NP | ZDIVO Z CDm 0.125 m | 1 | ZDIVO Z CDm | A | 1452HWa1096117376 | m3 | Celá stěna | Stávající | Zednické práce | ZDIVO Z CDm |  | 1452Stě1096117377 | m3 | Stěna | 0 | 0.125 | 0.168 | 0.168 | 0.021 | 0.05 | 0.021 | 0.006 | 3.35
ZDIVO Z CDm | Půdorys 1.NP | ZDIVO Z CDm 0.125 m | 1 | ZDIVO Z CDm | A | 1452HWa1096117523 | m3 | Celá stěna | Stávající | Zednické práce | ZDIVO Z CDm |  | 1452Stě1096117524 | m3 | Stěna | 0 | 0.125 | 1.759 | 1.759 | 0.22 | 0.525 | 0.22 | 0.066 | 3.35
ZDIVO Z CDm | Půdorys 1.NP | ZDIVO Z CDm 0.125 m | 1 | ZDIVO Z CDm | A | 1452HWa1096117528 | m3 | Celá stěna | Stávající | Zednické práce | ZDIVO Z CDm |  | 1452Stě1096117529 | m3 | Stěna | 0 | 0.125 | 3.115 | 3.116 | 0.389 | 0.93 | 0.389 | 0.116 | 3.35
ZDIVO Z CDm | Půdorys 1.NP | ZDIVO Z CDm 0.125 m | 1 | ZDIVO Z CDm | A | 1452HWa1096117542 | m3 | Celá stěna | Stávající | Zednické práce | ZDIVO Z CDm |  | 1452Stě1096117543 | m3 | Stěna | 0 | 0.125 | 1.34 | 1.34 | 0.168 | 0.4 | 0.168 | 0.05 | 3.35
YTONG 100 | Půdorys 1.NP | YTONG 100 0.1 m | 1 | YTONG 100 | EI 120 | 1452HWa1096117554 | m3 | Celá stěna | Stávající | Zednické práce | YTONG 100 |  | 1452Stě1096117555 | m2 | Stěna | 1.111 | 0.1 | 3.534 | 3.534 | 0.353 | 1.055 | 0.353 | 0.105 | 3.35 | Pset_WallCommon - AcousticRating: 37 dB
YTONG 100 | Půdorys 1.NP | YTONG 100 0.1 m | 1 | YTONG 100 | EI 120 | 1452HWa1096117568 | m3 | Celá stěna | Stávající | Zednické práce | YTONG 100 |  | 1452Stě1096117569 | m2 | Stěna | 1.111 | 0.1 | 1.775 | 1.776 | 0.178 | 0.53 | 0.178 | 0.053 | 3.35 | Pset_WallCommon - AcousticRating: 37 dB
ZDIVO Z CDm | Půdorys 1.NP | ZDIVO Z CDm 0.125 m | 1 | ZDIVO Z CDm | A | 1452HWa1096117577 | m3 | Celá stěna | Stávající | Zednické práce | ZDIVO Z CDm |  | 1452Stě1096117578 | m3 | Stěna | 0 | 0.125 | 2.446 | 2.446 | 0.306 | 0.73 | 0.306 | 0.091 | 3.35
YTONG 150 | Půdorys 1.NP | YTONG 150 0.15 m | 1 | YTONG 150 | EI 180 | 1452HWa1096117698 | m3 | Celá stěna | Stávající | Zednické práce | YTONG 150 |  | 1452Stě1096117699 | m2 | Stěna | 0.794 | 0.15 | 10.971 | 10.971 | 1.646 | 3.275 | 1.646 | 0.491 | 3.35 | Pset_WallCommon - AcousticRating: 41 dB
YTONG 125 | Půdorys 1.NP | YTONG 125 0.125 m | 1 | YTONG 125 | EI 180 | 1452HWa1096117708 | m3 | Celá stěna | Stávající | Zednické práce | YTONG 125 |  | 1452Stě1096117709 | m2 | Stěna | 0.926 | 0.125 | 7 | 7 | 0.875 | 2 | 0.875 | 0.25 | 3.5 | Pset_WallCommon - AcousticRating: 39 dB
ZDIVO Z CDm | Půdorys 1.NP | ZDIVO Z CDm 0.125 m | 1 | ZDIVO Z CDm | A | 1452HWa1096101607 | m3 | Celá stěna | Stávající | Zednické práce | ZDIVO Z CDm | yes | 1452Stě1096101608 | m3 | Stěna | 0 | 0.125 | 85.258 | 63.708 | 10.657 | 25.45 | 7.963 | 3.181 | 3.35
ZDIVO Z CDm | Půdorys 1.NP | ZDIVO Z CDm 0.125 m | 1 | ZDIVO Z CDm | A | 1452HWa1096117718 | m3 | Celá stěna | Stávající | Zednické práce | ZDIVO Z CDm | yes | 1452Stě1096117893 | m3 | Stěna | 0 | 0.125 | 19.497 | 13.439 | 2.437 | 5.82 | 1.73 | 0.728 | 3.35
ZDIVO Z CDm | Půdorys 1.NP | ZDIVO Z CDm 0.125 m | 1 | ZDIVO Z CDm | A | 1452HWa1096118047 | m3 | Celá stěna | Stávající | Zednické práce | ZDIVO Z CDm | yes | 1452Stě1096118049 | m3 | Stěna | 0 | 0.125 | 7.119 | 7.119 | 0.89 | 2.125 | 0.89 | 0.266 | 3.35
YTONG 100 | Půdorys 1.NP | YTONG 100 0.1 m | 1 | YTONG 100 | EI 120 | 1452HWa1096118099 | m3 | Celá stěna | Stávající | Zednické práce | YTONG 100 |  | 1452Stě1096118100 | m2 | Stěna | 1.111 | 0.1 | 3.35 | 3.35 | 0.335 | 1 | 0.335 | 0.1 | 3.35 | Pset_WallCommon - AcousticRating: 37 dB
YTONG 100 | Půdorys 1.NP | YTONG 100 0.1 m | 1 | YTONG 100 | EI 120 | 1452HWa1096118109 | m3 | Celá stěna | Stávající | Zednické práce | YTONG 100 |  | 1452Stě1096118110 | m2 | Stěna | 1.111 | 0.1 | 6.114 | 4.498 | 0.611 | 1.825 | 0.45 | 0.183 | 3.35 | Pset_WallCommon - AcousticRating: 37 dB
YTONG 125 | Půdorys 1.NP | YTONG 125 0.125 m | 1 | YTONG 125 | EI 180 | 1452HWa1096112788 | m3 | Celá stěna | Stávající | Zednické práce | YTONG 125 | no | 1452Stě1096112799 | m2 | Stěna | 0.926 | 0.125 | 11.113 | 6.995 | 1.389 | 3.175 | 0.936 | 0.397 | 3.5 | Pset_WallCommon - AcousticRating: 39 dB
YTONG 150 | Půdorys 1.NP | YTONG 150 0.15 m | 1 | YTONG 150 | EI 180 | 1452HWa1096117974 | m3 | Celá stěna | Stávající | Zednické práce | YTONG 150 |  | 1452Stě1096117975 | m2 | Stěna | 0.794 | 0.15 | 5.109 | 5.109 | 0.766 | 1.525 | 0.766 | 0.229 | 3.35 | Pset_WallCommon - AcousticRating: 41 dB
ZDIVO Z CDm | Půdorys 1.NP | ZDIVO Z CDm 0.125 m | 1 | ZDIVO Z CDm | A | 1452HWa1096118032 | m3 | Celá stěna | Stávající | Zednické práce | ZDIVO Z CDm | yes | 1452Stě1096118033 | m3 | Stěna | 0 | 0.125 | 5.192 | 5.193 | 0.649 | 1.55 | 0.649 | 0.194 | 3.35
YTONG 100 | Půdorys 1.NP | YTONG 100 0.1 m | 1 | YTONG 100 | EI 120 | 1452HWa1096118226 | m3 | Celá stěna | Stávající | Zednické práce | YTONG 100 |  | 1452Stě1096118227 | m2 | Stěna | 1.111 | 0.1 | 6.114 | 4.498 | 0.611 | 1.825 | 0.45 | 0.183 | 3.35 | Pset_WallCommon - AcousticRating: 37 dB
YTONG 150 | Půdorys 1.NP | YTONG 150 0.15 m | 1 | YTONG 150 | EI 180 | 1452HWa1096118492 | m3 | Celá stěna | Stávající | Zednické práce | YTONG 150 |  | 1452Stě1096118493 | m2 | Stěna | 0.794 | 0.15 | 7.872 | 7.873 | 1.181 | 2.35 | 1.181 | 0.352 | 3.35 | Pset_WallCommon - AcousticRating: 41 dB
YTONG 100 | Půdorys 1.NP | YTONG 100 0.1 m | 1 | YTONG 100 | EI 120 | 1452HWa1096118507 | m3 | Celá stěna | Stávající | Zednické práce | YTONG 100 |  | 1452Stě1096118508 | m2 | Stěna | 1.111 | 0.1 | 4.02 | 2.404 | 0.402 | 1.2 | 0.24 | 0.12 | 3.35 | Pset_WallCommon - AcousticRating: 37 dB
YTONG 125 | Půdorys 1.NP | YTONG 125 0.125 m | 1 | YTONG 125 | EI 180 | 1452HWa1096118517 | m3 | Celá stěna | Stávající | Zednické práce | YTONG 125 |  | 1452Stě1096118518 | m2 | Stěna | 0.926 | 0.125 | 4.025 | 4.025 | 0.503 | 1.15 | 0.503 | 0.144 | 3.5 | Pset_WallCommon - AcousticRating: 39 dB
ZDIVO Z CDm | Půdorys 1.NP | ZDIVO Z CDm 0.125 m | 1 | ZDIVO Z CDm | A | 1452HWa1096118929 | m3 | Celá stěna | Stávající | Zednické práce | ZDIVO Z CDm | yes | 1452Stě1096118930 | m3 | Stěna | 0 | 0.125 | 19.681 | 12.204 | 2.46 | 5.875 | 1.526 | 0.734 | 3.35
ZDIVO Z CDm | Půdorys 1.NP | ZDIVO Z CDm 0.125 m | 1 | ZDIVO Z CDm | A | 1452HWa1096118944 | m3 | Celá stěna | Stávající | Zednické práce | ZDIVO Z CDm | yes | 1452Stě1096118945 | m3 | Stěna | 0 | 0.125 | 3.685 | 2.965 | 0.461 | 1.1 | 0.371 | 0.137 | 3.35
ZDIVO Z CDm | Půdorys 1.NP | ZDIVO Z CDm 0.125 m | 1 | ZDIVO Z CDm | A | 1452HWa1096118934 | m3 | Celá stěna | Stávající | Zednické práce | ZDIVO Z CDm | yes | 1452Stě1096118935 | m3 | Stěna | 0 | 0.125 | 2.261 | 2.261 | 0.283 | 0.675 | 0.283 | 0.084 | 3.35
ZDIVO Z CDm | Půdorys 1.NP | ZDIVO Z CDm 0.125 m | 1 | ZDIVO Z CDm | A | 1452HWa1096118996 | m3 | Celá stěna | Stávající | Zednické práce | ZDIVO Z CDm | yes | 1452Stě1096118997 | m3 | Stěna | 0 | 0.125 | 1.507 | 1.508 | 0.188 | 0.45 | 0.188 | 0.056 | 3.35
ZDIVO Z CDm | Půdorys 1.NP | ZDIVO Z CDm 0.125 m | 1 | ZDIVO Z CDm | A | 1452HWa1096119010 | m3 | Celá stěna | Stávající | Zednické práce | ZDIVO Z CDm | yes | 1452Stě1096119011 | m3 | Stěna | 0 | 0.125 | 4.104 | 4.104 | 0.513 | 1.225 | 0.513 | 0.153 | 3.35
ZDIVO Z CDm | Půdorys 1.NP | ZDIVO Z CDm 0.125 m | 1 | ZDIVO Z CDm | A | 1452HWa1096119015 | m3 | Celá stěna | Stávající | Zednické práce | ZDIVO Z CDm | yes | 1452Stě1096119016 | m3 | Stěna | 0 | 0.125 | 2.01 | 2.01 | 0.251 | 0.6 | 0.251 | 0.075 | 3.35
ZDIVO Z CDm | Půdorys 1.NP | ZDIVO Z CDm 0.125 m | 1 | ZDIVO Z CDm | A | 1452HWa1096119076 | m3 | Celá stěna | Stávající | Zednické práce | ZDIVO Z CDm | yes | 1452Stě1096119077 | m3 | Stěna | 0 | 0.125 | 2.261 | 2.261 | 0.283 | 0.675 | 0.283 | 0.084 | 3.35
YTONG 100 | Půdorys 1.NP | YTONG 100 0.1 m | 1 | YTONG 100 | EI 120 | 1452HWa1096119120 | m3 | Celá stěna | Stávající | Zednické práce | YTONG 100 |  | 1452Stě1096119121 | m2 | Stěna | 1.111 | 0.1 | 1.926 | 1.926 | 0.193 | 0.575 | 0.193 | 0.058 | 3.35 | Pset_WallCommon - AcousticRating: 37 dB
YTONG 150 | Půdorys 1.NP | YTONG 150 0.15 m |  | YTONG 150 | EI 180 | 1452HWa1096119137 | m3 | Celá stěna | Stávající | Zednické práce | YTONG 150 |  | 1452Stě1096119138 | m2 | Stěna | 0.794 | 0.15 | 9.631 | 5.891 | 1.445 | 2.875 | 0.884 | 0.431 | 3.35 | Pset_WallCommon - AcousticRating: 41 dB
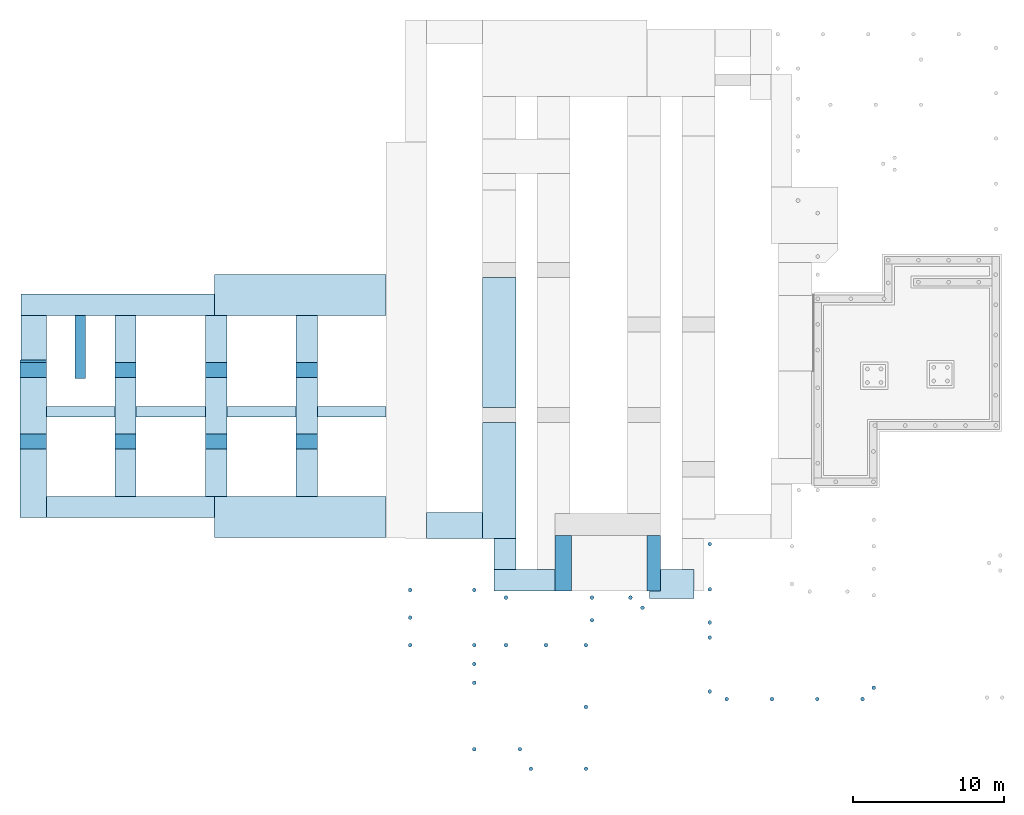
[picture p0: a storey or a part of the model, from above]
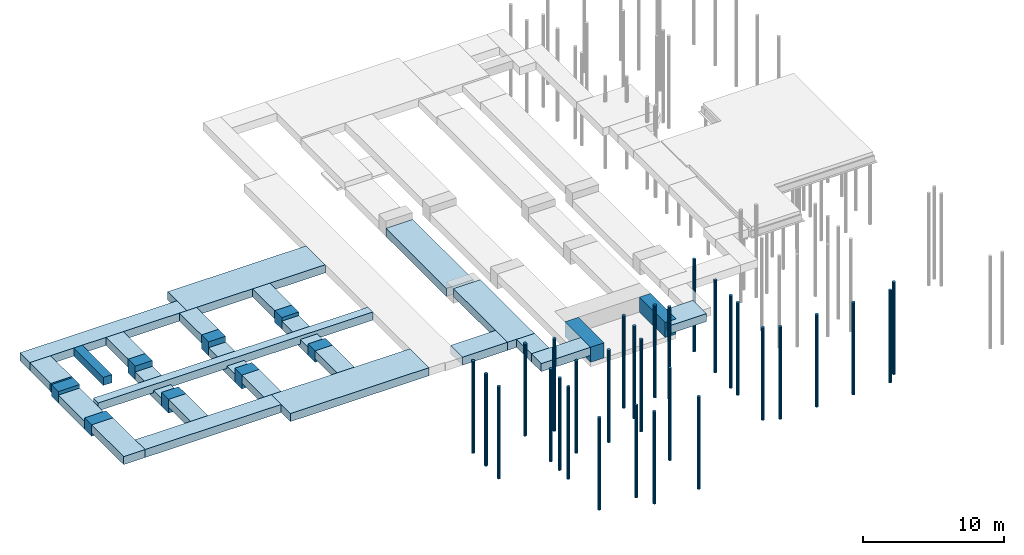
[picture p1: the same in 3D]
Properties of the parts of a building model (IFC4), part 32 of 45

# IfcWall (2385)
Name | In | Material | Faktor | Označení | Požární odolnost | Allright_Stavebni_dil_ID | Jednotka | Název_objektu | Object Layer Attributes #1, Status | Object Layer Attributes #1, Práce | Object Layer Attributes #1, Materiál | Object Layer Attributes #1, Staticky nosná konstrukce | Object Layer Attributes #1, Allright_Stavebni_dil_ID | Object Layer Attributes #1, Jednotka | Object Layer Attributes #1, Název_objektu | ThermalTransmittance (W/K/m2) | Width (m) | GrossSideArea (m2) | NetSideArea (m2) | GrossVolume (m3) | Length (m) | NetVolume (m3) | GrossFootprintArea (m2) | Height (m)
ZDIVO Z CDm | Půdorys 1.NP | ZDIVO Z CDm 0.125 m | 1 | ZDIVO Z CDm | A | 1452HWa0798424487 | m3 | Celá stěna | Stávající | Zednické práce | ZDIVO Z CDm | yes | 1452Stě0798424498 | m3 | Stěna | 0 | 0.125 | 7.621 | 4.49 | 0.953 | 2.275 | 0.561 | 0.284 | 3.35
ZDIVO Z CDm | Půdorys 1.NP | ZDIVO Z CDm 0.2 m | 1 | ZDIVO Z CDm | A | 1452HWa1096131707 | m3 | Celá stěna | Stávající | Zednické práce | ZDIVO Z CDm | yes | 1452Stě1096131713 | m3 | Stěna | 0 | 0.2 | 1.508 | 1.508 | 0.302 | 0.45 | 0.302 | 0.09 | 3.35
ZDIVO Z CDm | Půdorys 1.NP | ZDIVO Z CDm 0.125 m | 1 | ZDIVO Z CDm | A | 1452HWa1096114815 | m3 | Celá stěna | Stávající | Zednické práce | ZDIVO Z CDm |  | 1452Stě1096114816 | m3 | Stěna | 0 | 0.125 | 6.533 | 4.432 | 0.817 | 1.95 | 0.554 | 0.244 | 3.35
STÁVAJÍCÍ KCE | Půdorys 1.NP | STÁVAJÍC KCE 0.1 m | 1 | STÁVAJÍCÍ KCE | REI 180 | 1452HWa1096107600 | m3 | Celá stěna | Stávající | Zednické práce | STÁVAJÍC KCE | yes | 1452Stě1096107601 | m3 | Stěna | 0.541 | 0.1 | 0.502 | 0.503 | 0.05 | 0.15 | 0.05 | 0.015 | 3.35 | Pset_WallCommon - AcousticRating: 48 dB
STÁVAJÍCÍ KCE | Půdorys 1.NP | STÁVAJÍC KCE 0.1 m | 1 | STÁVAJÍCÍ KCE | REI 180 | 1452HWa1096107620 | m3 | Celá stěna | Stávající | Zednické práce | STÁVAJÍC KCE | yes | 1452Stě1096107621 | m3 | Stěna | 0.541 | 0.1 | 0.502 | 0.503 | 0.05 | 0.15 | 0.05 | 0.015 | 3.35 | Pset_WallCommon - AcousticRating: 48 dB
ZELEZOBETONOVÁ KCE | Půdorys 1.NP | ZELEZOBETONOVÁ KCE 0.3 m | 1 | ZELEZOBETONOVÁ KCE | A | 1452HWa0798418566 | m3 | Celá stěna | Stávající | Betonářské práce | ZELEZOBETONOVÁ KCE |  | 1452Stě0798418567 | m3 | Stěna | 0 | 0.3 | 11.88 | 11.88 | 3.564 | 3.3 | 3.564 | 0.99 | 3.6
EPS | Půdorys 1.NP | EPS 0.1 m | 1 | EPS |  | 1452HWa0798442478 | m3 | Celá stěna | Stávající | Zateplovací systémy | EPS |  | 1452Stě0798442479 | m2 | Stěna |  | 0.1 | 7.378 | 7.378 | 0.738 | 2.38 | 0.738 | 0.238 | 3.1
PLYNOSILIKÁT | Půdorys 1.NP | PLYNOSILIKÁT 0.32 m | 1 | PLYNOSILIKÁT | REI 180 | 1452HWa0798418199 | m3 | Celá stěna | Stávající | Zednické práce | PLYNOSILIKÁT |  | 1452Stě0798418200 | m3 | Stěna | 0.541 | 0.32 | 2.592 | 2.592 | 0.829 | 0.72 | 0.829 | 0.23 | 3.6 | Pset_WallCommon - AcousticRating: 48 dB
PLYNOSILIKÁT | Půdorys 1.NP | PLYNOSILIKÁT 0.32 m | 1 | PLYNOSILIKÁT | REI 180 | 1452HWa1096132762 | m3 | Celá stěna | Stávající | Zednické práce | PLYNOSILIKÁT |  | 1452Stě1096132767 | m3 | Stěna | 0.541 | 0.32 | 5.4 | 1.077 | 1.728 | 1.5 | 0.345 | 0.48 | 3.6 | Pset_WallCommon - AcousticRating: 48 dB
PLYNOSILIKÁT | Půdorys 1.NP | PLYNOSILIKÁT 0.32 m | 1 | PLYNOSILIKÁT | REI 180 | 1452HWa1096132734 | m3 | Celá stěna | Stávající | Zednické práce | PLYNOSILIKÁT |  | 1452Stě1096132740 | m3 | Stěna | 0.541 | 0.32 | 3.888 | 2.802 | 1.244 | 1.08 | 0.85 | 0.346 | 3.6 | Pset_WallCommon - AcousticRating: 48 dB
ZELEZOBETONOVÁ KCE | Půdorys 1.NP | ZELEZOBETONOVÁ KCE 0.15 m | 1 | ZELEZOBETONOVÁ KCE | A | 1452HWa1096133061 | m3 | Celá stěna | Stávající | Betonářské práce | ZELEZOBETONOVÁ KCE |  | 1452Stě1096133063 | m3 | Stěna | 0 | 0.15 | 0.17 | 0.17 | 0.025 | 0.85 | 0.025 | 0.127 | 0.2
ZELEZOBETONOVÁ KCE | Půdorys 1.NP | ZELEZOBETONOVÁ KCE 0.15 m | 1 | ZELEZOBETONOVÁ KCE | A | 1452HWa1096133094 | m3 | Celá stěna | Stávající | Betonářské práce | ZELEZOBETONOVÁ KCE |  | 1452Stě1096133095 | m3 | Stěna | 0 | 0.15 | 0.17 | 0.17 | 0.025 | 0.85 | 0.025 | 0.127 | 0.2
ZELEZOBETONOVÁ KCE | Půdorys 1.NP | ZELEZOBETONOVÁ KCE 0.15 m | 1 | ZELEZOBETONOVÁ KCE | A | 1452HWa1096133083 | m3 | Celá stěna | Stávající | Betonářské práce | ZELEZOBETONOVÁ KCE |  | 1452Stě1096133084 | m3 | Stěna | 0 | 0.15 | 0.17 | 0.17 | 0.025 | 0.85 | 0.025 | 0.127 | 0.2
ZELEZOBETONOVÁ KCE | Půdorys 1.NP | ZELEZOBETONOVÁ KCE 0.15 m |  | ZELEZOBETONOVÁ KCE | A | 1452HWa1096133073 | m3 | Celá stěna | Stávající | Betonářské práce | ZELEZOBETONOVÁ KCE |  | 1452Stě1096133074 | m3 | Stěna | 0 | 0.15 | 0.17 | 0.17 | 0.025 | 0.85 | 0.025 | 0.127 | 0.2
ZDIVO Z CDm | Půdorys 1.NP | ZDIVO Z CDm 0.125 m | 1 | ZDIVO Z CDm | A | 1452HWa1096132303 | m3 | Celá stěna | Stávající | Zednické práce | ZDIVO Z CDm | yes | 1452Stě1096132322 | m3 | Stěna | 0 | 0.125 | 12.897 | 12.898 | 1.612 | 3.85 | 1.612 | 0.481 | 3.35
ZELEZOBETONOVÁ KCE | Půdorys 1.NP | ZELEZOBETONOVÁ KCE 0.65 m | 1 | ZELEZOBETONOVÁ KCE | A | 1452HWa0000002567 | m3 | Celá stěna | Stávající | Betonářské práce | ZELEZOBETONOVÁ KCE |  | 1452Stě0000002568 | m3 | Stěna | 0 | 0.65 | 12.589 | 12.59 | 8.183 | 3.27 | 8.183 | 2.125 | 3.85 | Pset_WallCommon - LoadBearing: yes
STÁVAJÍCÍ KCE | Půdorys 1.NP | STÁVAJÍC KCE | 1 | STÁVAJÍCÍ KCE | REI 180 | 1452HWa0798429896 | m3 | Celá stěna | Stávající | Zednické práce | STÁVAJÍC KCE | yes | 1452Stě0798429897 | m3 | Stěna | 0.541 | 0.4 | 32.83 | 22.398 | 13.132 | 9.8 | 8.964 | 3.92 | 3.35 | Pset_WallCommon - AcousticRating: 48 dB
ZELEZOBETONOVÁ KCE | Půdorys 1.NP | ZELEZOBETONOVÁ KCE 0.32 m, EPS 0.1 m |  | ZELEZOBETONOVÁ KCE | A | 1452HWa0000002508 | m3 | Celá stěna | Stávající | Betonářské práce | ZELEZOBETONOVÁ KCE |  | 1452Stě0000002511 | m3 | Stěna | 0 | 0.42 | 60.83 | 54.08 | 23.146 | 15.9 | 20.356 | 6.656 | 3.85 | NEMSOK - Object Layer Attributes #2, 2D interakce: yes; Object Layer Attributes #2, Status: Stávající; Object Layer Attributes #2, Práce: Zateplovací systémy; Object Layer Attributes #2, Materiál: EPS; Object Layer Attributes #2, Allright_Stavebni_dil_ID: 1452Stě1096106566; Object Layer Attributes #2, Jednotka: m2; Object Layer Attributes #2, Název_objektu: Stěna; Pset_WallCommon - LoadBearing: yes
ZELEZOBETONOVÁ KCE | Půdorys 1.NP | ZELEZOBETONOVÁ KCE 0.2 m, EPS 0.1 m |  | ZELEZOBETONOVÁ KCE | A | 1452HWa0000002546 | m3 | Celá stěna | Stávající | Betonářské práce | ZELEZOBETONOVÁ KCE |  | 1452Stě0000002547 | m3 | Stěna | 0 | 0.3 | 4.12 | 4.12 | 0.99 | 0.895 | 0.99 | 0.286 | 3.85 | NEMSOK - Object Layer Attributes #2, 2D interakce: yes; Object Layer Attributes #2, Status: Stávající; Object Layer Attributes #2, Práce: Zateplovací systémy; Object Layer Attributes #2, Materiál: EPS; Object Layer Attributes #2, Allright_Stavebni_dil_ID: 1452Stě1096106173; Object Layer Attributes #2, Jednotka: m2; Object Layer Attributes #2, Název_objektu: Stěna; Pset_WallCommon - LoadBearing: yes
ZELEZOBETONOVÁ KCE | Půdorys 1.NP | ZELEZOBETONOVÁ KCE 0.45 m, EPS 0.1 m |  | ZELEZOBETONOVÁ KCE | A | 1452HWa0000002538 | m3 | Celá stěna | Stávající | Betonářské práce | ZELEZOBETONOVÁ KCE |  | 1452Stě0000002539 | m3 | Stěna | 0 | 0.55 | 29.26 | 26.629 | 15.041 | 7.875 | 13.684 | 4.235 | 3.85 | NEMSOK - Object Layer Attributes #2, 2D interakce: yes; Object Layer Attributes #2, Status: Stávající; Object Layer Attributes #2, Práce: Zateplovací systémy; Object Layer Attributes #2, Materiál: EPS; Object Layer Attributes #2, Allright_Stavebni_dil_ID: 1452Stě1096106396; Object Layer Attributes #2, Jednotka: m2; Object Layer Attributes #2, Název_objektu: Stěna; Pset_WallCommon - LoadBearing: yes
ZELEZOBETONOVÁ KCE | Půdorys 1.NP | ZELEZOBETONOVÁ KCE 0.32 m |  | ZELEZOBETONOVÁ KCE | A | 1452HWa1096134470 | m3 | Celá stěna | Stávající | Betonářské práce | ZELEZOBETONOVÁ KCE |  | 1452Stě1096134480 | m3 | Stěna | 0 | 0.32 | 8.568 | 2.448 | 2.742 | 4.2 | 0.783 | 1.344 | 2.04
ZELEZOBETONOVÁ KCE | Půdorys 1.NP | ZELEZOBETONOVÁ KCE 0.32 m |  | ZELEZOBETONOVÁ KCE | A | 1452HWa1096134596 | m3 | Celá stěna | Stávající | Betonářské práce | ZELEZOBETONOVÁ KCE |  | 1452Stě1096134597 | m3 | Stěna | 0 | 0.32 | 6.102 | 6.094 | 1.953 | 5.4 | 1.918 | 1.728 | 1.13
PLYNOSILIKÁT | Půdorys 1.NP | PLYNOSILIKÁT 0.32 m | 1 | PLYNOSILIKÁT | REI 180 | 1452HWa1096134624 | m3 | Celá stěna | Stávající | Zednické práce | PLYNOSILIKÁT |  | 1452Stě1096134625 | m3 | Stěna | 0.541 | 0.32 | 2.448 | 2.448 | 0.783 | 1.2 | 0.726 | 0.384 | 2.04 | Pset_WallCommon - AcousticRating: 48 dB
ZELEZOBETONOVÁ KCE | Půdorys 1.NP | ZELEZOBETONOVÁ KCE 0.32 m |  | ZELEZOBETONOVÁ KCE | A | 1452HWa1096134632 | m3 | Celá stěna | Stávající | Betonářské práce | ZELEZOBETONOVÁ KCE |  | 1452Stě1096134639 | m3 | Stěna | 0 | 0.32 | 9.51 | 4.88 | 3.043 | 3 | 1.517 | 0.96 | 3.17
ZELEZOBETONOVÁ KCE | Půdorys 1.NP | ZELEZOBETONOVÁ KCE 0.27 m |  | ZELEZOBETONOVÁ KCE | A | 1452HWa0000002653 | m3 | Celá stěna | Stávající | Betonářské práce | ZELEZOBETONOVÁ KCE |  | 1452Stě0000002654 | m3 | Stěna | 0 | 0.27 | 5.583 | 5.583 | 1.507 | 1.45 | 1.507 | 0.392 | 3.85 | Pset_WallCommon - LoadBearing: yes
ZDIVO Z CDm | Půdorys 1.NP | ZDIVO Z CDm 0.125 m | 1 | ZDIVO Z CDm | A | 1452HWa1096220415 | m3 | Celá stěna | Stávající | Zednické práce | ZDIVO Z CDm |  | 1452Stě1096220417 | m3 | Stěna | 0 | 0.125 | 1.759 | 1.759 | 0.22 | 0.525 | 0.22 | 0.066 | 3.35
YTONG 125 | Půdorys 1.NP | YTONG 125 0.125 m | 1 | YTONG 125 | EI 180 | 1452HWa0798441864 | m3 | Celá stěna | Stávající | Zednické práce | YTONG 125 |  | 1452Stě0798441865 | m2 | Stěna | 0.926 | 0.125 | 10.05 | 7.175 | 1.256 | 3 | 0.897 | 0.375 | 3.35 | Pset_WallCommon - AcousticRating: 39 dB
ZDIVO Z CDm | Půdorys 1.NP | ZDIVO Z CDm 0.125 m | 1 | ZDIVO Z CDm | A | 1452HWa0798430826 | m3 | Celá stěna | Stávající | Zednické práce | ZDIVO Z CDm | yes | 1452Stě0798430827 | m3 | Stěna | 0 | 0.125 | 54.689 | 50.677 | 6.836 | 16.325 | 6.335 | 2.041 | 3.35
 | Půdorys 1.NP | ZELEZOBETONOVÁ KCE 0.5 m |  |  |  | 1454HWa0000000009 | m3 | Celá stěna | Stávající | Betonářské práce | ZELEZOBETONOVÁ KCE | yes | 1454Ven0000000039 | m2 | Věnec |  | 0.5 | 1.888 | 1.888 | 0.944 | 0 | 0.944 | 3.775 | 0.25
 | Půdorys 1.NP | ZELEZOBETONOVÁ KCE 0.5 m |  |  |  | 1454HWa0000000018 | m3 | Celá stěna | Stávající | Betonářské práce | ZELEZOBETONOVÁ KCE | yes | 1454Ven0000000065 | m2 | Věnec |  | 0.5 | 1.888 | 1.888 | 0.944 | 0 | 0.944 | 3.775 | 0.25
 | Půdorys 1.NP | ZELEZOBETONOVÁ KCE 0.5 m |  |  |  | 1454HWa0000000007 | m3 | Celá stěna | Stávající | Betonářské práce | ZELEZOBETONOVÁ KCE | yes | 1454Ven0000000043 | m2 | Věnec |  | 0.5 | 0.75 | 0.75 | 0.375 | 0 | 0.375 | 1.5 | 0.25
EPS | Půdorys 1.NP | EPS 0.1 m |  | EPS |  | 1454HWa0000001267 | m3 | Celá stěna | Stávající | Zateplovací systémy | EPS | no | 1454Stě0000001268 | m2 | Stěna |  | 0.1 | 0.55 | 0.55 | 0.055 | 2.2 | 0.055 | 0.22 | 0.25
EPS | Půdorys 1.NP | EPS 0.1 m |  | EPS |  | 1454HWa0000001282 | m3 | Celá stěna | Stávající | Zateplovací systémy | EPS | no | 1454Stě0000001284 | m2 | Stěna |  | 0.1 | 1.15 | 1.15 | 0.115 | 4.6 | 0.115 | 0.46 | 0.25
EPS | Půdorys 1.NP | EPS 0.1 m |  | EPS |  | 1454HWa0000001295 | m3 | Celá stěna | Stávající | Zateplovací systémy | EPS | no | 1454Stě0000001297 | m2 | Stěna |  | 0.1 | 1.15 | 1.15 | 0.115 | 4.6 | 0.115 | 0.46 | 0.25
 | Půdorys 1.NP | ZELEZOBETONOVÁ KCE 0.45 m, LIGNOPOR 0.05 m |  |  |  | 1454HWa0000000002 | m3 | Celá stěna | Stávající | Betonářské práce | ZELEZOBETONOVÁ KCE | yes | 1454Ven0000000029 | m2 | Věnec |  | 0.5 | 0.837 | 0.838 | 0.362 | 0 | 0.362 | 1.45 | 0.25 | NEMSOK - Object Layer Attributes #2, 2D interakce: yes; Object Layer Attributes #2, Status: Stávající; Object Layer Attributes #2, Práce: Zateplovací systémy; Object Layer Attributes #2, Materiál: LIGNOPOR; Object Layer Attributes #2, Allright_Stavebni_dil_ID: 1454Ven0000000025; Object Layer Attributes #2, Jednotka: m2; Object Layer Attributes #2, Název_objektu: Věnec; Object Layer Attributes #2, Staticky nosná konstrukce: no
 | Půdorys 1.NP | ZELEZOBETONOVÁ KCE 0.45 m, LIGNOPOR 0.05 m |  |  |  | 1454HWa0000000004 | m3 | Celá stěna | Stávající | Betonářské práce | ZELEZOBETONOVÁ KCE | yes | 1454Ven0000000041 | m2 | Věnec |  | 0.5 | 0.188 | 0.188 | 0.049 | 0 | 0.049 | 0.195 | 0.25 | NEMSOK - Object Layer Attributes #2, 2D interakce: yes; Object Layer Attributes #2, Status: Stávající; Object Layer Attributes #2, Práce: Zateplovací systémy; Object Layer Attributes #2, Materiál: LIGNOPOR; Object Layer Attributes #2, Allright_Stavebni_dil_ID: 1454Ven0000000055; Object Layer Attributes #2, Jednotka: m2; Object Layer Attributes #2, Název_objektu: Věnec; Object Layer Attributes #2, Staticky nosná konstrukce: no
 | Půdorys 1.NP | ZELEZOBETONOVÁ KCE 0.45 m, LIGNOPOR 0.05 m |  |  |  | 1454HWa0000000005 | m3 | Celá stěna | Stávající | Betonářské práce | ZELEZOBETONOVÁ KCE | yes | 1454Ven0000000037 | m2 | Věnec |  | 0.5 | 1.775 | 1.775 | 0.887 | 0 | 0.887 | 3.55 | 0.25 | NEMSOK - Object Layer Attributes #2, 2D interakce: yes; Object Layer Attributes #2, Status: Stávající; Object Layer Attributes #2, Práce: Zateplovací systémy; Object Layer Attributes #2, Materiál: LIGNOPOR; Object Layer Attributes #2, Allright_Stavebni_dil_ID: 1454Ven0000000053; Object Layer Attributes #2, Jednotka: m2; Object Layer Attributes #2, Název_objektu: Věnec; Object Layer Attributes #2, Staticky nosná konstrukce: no
 | Půdorys 1.NP | ZELEZOBETONOVÁ KCE 0.45 m, LIGNOPOR 0.05 m |  |  |  | 1454HWa0000000014 | m3 | Celá stěna | Stávající | Betonářské práce | ZELEZOBETONOVÁ KCE | yes | 1454Ven0000000067 | m2 | Věnec |  | 0.5 | 2.125 | 2.125 | 1.006 | 0 | 1.006 | 4.025 | 0.25 | NEMSOK - Object Layer Attributes #2, 2D interakce: yes; Object Layer Attributes #2, Status: Stávající; Object Layer Attributes #2, Práce: Zateplovací systémy; Object Layer Attributes #2, Materiál: LIGNOPOR; Object Layer Attributes #2, Allright_Stavebni_dil_ID: 1454Ven0000000047; Object Layer Attributes #2, Jednotka: m2; Object Layer Attributes #2, Název_objektu: Věnec; Object Layer Attributes #2, Staticky nosná konstrukce: no
 | Půdorys 1.NP | ZELEZOBETONOVÁ KCE 0.45 m, LIGNOPOR 0.05 m |  |  |  | 1454HWa0000000008 | m3 | Celá stěna | Stávající | Betonářské práce | ZELEZOBETONOVÁ KCE | yes | 1454Ven0000000031 | m2 | Věnec |  | 0.5 | 2.625 | 2.625 | 1.301 | 0 | 1.301 | 5.205 | 0.25 | NEMSOK - Object Layer Attributes #2, 2D interakce: yes; Object Layer Attributes #2, Status: Stávající; Object Layer Attributes #2, Práce: Zateplovací systémy; Object Layer Attributes #2, Materiál: LIGNOPOR; Object Layer Attributes #2, Allright_Stavebni_dil_ID: 1454Ven0000000027; Object Layer Attributes #2, Jednotka: m2; Object Layer Attributes #2, Název_objektu: Věnec; Object Layer Attributes #2, Staticky nosná konstrukce: no
 | Půdorys 1.NP | ZELEZOBETONOVÁ KCE 0.45 m, LIGNOPOR 0.05 m |  |  |  | 1454HWa0000000022 | m3 | Celá stěna | Stávající | Betonářské práce | ZELEZOBETONOVÁ KCE | yes | 1454Ven0000000035 | m2 | Věnec |  | 0.5 | 2.325 | 2.325 | 1.106 | 0 | 1.106 | 4.425 | 0.25 | NEMSOK - Object Layer Attributes #2, 2D interakce: yes; Object Layer Attributes #2, Status: Stávající; Object Layer Attributes #2, Práce: Zateplovací systémy; Object Layer Attributes #2, Materiál: LIGNOPOR; Object Layer Attributes #2, Allright_Stavebni_dil_ID: 1454Ven0000000033; Object Layer Attributes #2, Jednotka: m2; Object Layer Attributes #2, Název_objektu: Věnec; Object Layer Attributes #2, Staticky nosná konstrukce: no
ZELEZOBETONOVÁ KCE | Půdorys 1.NP | ZELEZOBETONOVÁ KCE 0.32 m |  | ZELEZOBETONOVÁ KCE | A | 1454HWa0000001755 | m3 | Celá stěna | Stávající | Betonářské práce | ZELEZOBETONOVÁ KCE |  | 1454Stě0000001756 | m3 | Stěna | 0 | 0.32 | 3.612 | 3.612 | 1.156 | 8.4 | 1.156 | 2.688 | 0.43
ZELEZOBETONOVÁ KCE | Půdorys 1.NP | ZELEZOBETONOVÁ KCE 0.32 m |  | ZELEZOBETONOVÁ KCE | A | 1454HWa0000001778 | m3 | Celá stěna | Stávající | Betonářské práce | ZELEZOBETONOVÁ KCE |  | 1454Stě0000001779 | m3 | Stěna | 0 | 0.32 | 6.708 | 6.708 | 2.147 | 15.6 | 2.147 | 4.992 | 0.43
ZDIVO Z CDm | Půdorys 1.NP | ZDIVO Z CDm 0.125 m |  | ZDIVO Z CDm | A | 1464HWa1096163879 | m3 | Celá stěna | Stávající | Zednické práce | ZDIVO Z CDm | yes | 1464Stě1096163898 | m3 | Stěna | 0 | 0.125 | 3.45 | 0 | 0.431 | 1.5 | 0 | 0.188 | 2.3
ZDIVO Z CDm | Půdorys 1.NP | ZDIVO Z CDm 0.125 m |  | ZDIVO Z CDm | A | 1464HWa1096207906 | m3 | Celá stěna | Stávající | Zednické práce | ZDIVO Z CDm | no | 1464Stě1096207907 | m3 | Stěna | 0 | 0.125 | 5.25 | 0 | 0.656 | 1.75 | 0 | 0.219 | 3
YTONG 150 | Půdorys 1.NP | YTONG 150 0.15 m |  | YTONG 150 | EI 180 | 1464HWa1096208796 | m3 | Celá stěna | Stávající | Zednické práce | YTONG 150 |  | 1464Stě1096208797 | m2 | Stěna | 0.794 | 0.15 | 3.22 | 0 | 0.483 | 1.4 | 0 | 0.21 | 2.3 | Pset_WallCommon - AcousticRating: 41 dB
PROSKLENÁ PŘÍČKA DVOJITÁ | Půdorys 1.NP | PROSKLENÁ PŘÍČKA DVOJITÁ 0.1 m |  | PROSKLENÁ PŘÍČKA DVOJITÁ | 0 | 1464HWa1096157003 | m3 | Celá stěna | Nový | Sklenářské práce | PROSKLENÁ PŘÍČKA DVOJITÁ | no | 1464Stě1096157304 | m3 | Stěna | 0 | 0.1 | 9.38 | 9.38 | 0.938 | 3.35 | 0.938 | 0.335 | 2.8 | Pset_WallCommon - AcousticRating: 0; NEMSOK - Object Layer Attributes #1, Kód prvku: SN11.03.0002; Object Layer Attributes #1, Podlaží: 1.NP; Object Layer Attributes #1, Funkce (venkovní): Ne; Object Layer Attributes #1, Součinitel prostupu tepla: 0; Object Layer Attributes #1, Vážená stavební neprůzvučnost: 47
PROSKLENÁ PŘÍČKA DVOJITÁ | Půdorys 1.NP | PROSKLENÁ PŘÍČKA DVOJITÁ 0.1 m |  | PROSKLENÁ PŘÍČKA DVOJITÁ | 0 | 1464HWa1096157013 | m3 | Celá stěna | Nový | Sklenářské práce | PROSKLENÁ PŘÍČKA DVOJITÁ | no | 1464Stě1096157549 | m3 | Stěna | 0 | 0.1 | 4.346 | 4.346 | 0.435 | 1.552 | 0.435 | 0.155 | 2.8 | Pset_WallCommon - AcousticRating: 0; NEMSOK - Object Layer Attributes #1, Kód prvku: SN11.03.0003; Object Layer Attributes #1, Podlaží: 1.NP; Object Layer Attributes #1, Funkce (venkovní): Ne; Object Layer Attributes #1, Součinitel prostupu tepla: 0; Object Layer Attributes #1, Vážená stavební neprůzvučnost: 47
PROSKLENÁ PŘÍČKA DVOJITÁ | Půdorys 1.NP | PROSKLENÁ PŘÍČKA DVOJITÁ 0.1 m |  | PROSKLENÁ PŘÍČKA DVOJITÁ | 0 | 1464HWa1096157015 | m3 | Celá stěna | Nový | Sklenářské práce | PROSKLENÁ PŘÍČKA DVOJITÁ | no | 1464Stě1096157018 | m3 | Stěna | 0 | 0.1 | 6.204 | 6.204 | 0.62 | 2.216 | 0.62 | 0.222 | 2.8 | Pset_WallCommon - AcousticRating: 0; NEMSOK - Object Layer Attributes #1, Kód prvku: SN11.03.0001; Object Layer Attributes #1, Podlaží: 1.NP; Object Layer Attributes #1, Funkce (venkovní): Ne; Object Layer Attributes #1, Součinitel prostupu tepla: 0; Object Layer Attributes #1, Vážená stavební neprůzvučnost: 47
PROSKLENÁ PŘÍČKA DVOJITÁ | Půdorys 1.NP | PROSKLENÁ PŘÍČKA DVOJITÁ 0.1 m |  | PROSKLENÁ PŘÍČKA DVOJITÁ | 0 | 1464HWa1096157019 | m3 | Celá stěna | Nový | Sklenářské práce | PROSKLENÁ PŘÍČKA DVOJITÁ | no | 1464Stě1096159651 | m3 | Stěna | 0 | 0.1 | 4.619 | 1.469 | 0.462 | 1.65 | 0.147 | 0.165 | 2.8 | Pset_WallCommon - AcousticRating: 0; NEMSOK - Object Layer Attributes #1, Kód prvku: SN11.03.0011; Object Layer Attributes #1, Podlaží: 1.NP; Object Layer Attributes #1, Funkce (venkovní): Ne; Object Layer Attributes #1, Součinitel prostupu tepla: 0; Object Layer Attributes #1, Vážená stavební neprůzvučnost: 47
PROSKLENÁ PŘÍČKA DVOJITÁ | Půdorys 1.NP | PROSKLENÁ PŘÍČKA PLNÝ PANEL 0.1 m |  | PROSKLENÁ PŘÍČKA DVOJITÁ | 0 | 1464HWa1096157527 | m3 | Celá stěna | Nový | Sklenářské práce | PROSKLENÁ PŘÍČKA PLNÝ PANEL | no | 1464Stě1096158060 | m3 | Stěna | 0 | 0.1 | 0.56 | 0.56 | 0.056 | 0.2 | 0.056 | 0.02 | 2.8 | Pset_WallCommon - AcousticRating: 0; NEMSOK - Object Layer Attributes #1, Kód prvku: SN11.03.0006; Object Layer Attributes #1, Podlaží: 1.NP; Object Layer Attributes #1, Funkce (venkovní): Ne; Object Layer Attributes #1, Součinitel prostupu tepla: 0; Object Layer Attributes #1, Vážená stavební neprůzvučnost: 47
PROSKLENÁ PŘÍČKA DVOJITÁ | Půdorys 1.NP | PROSKLENÁ PŘÍČKA PLNÝ PANEL 0.1 m |  | PROSKLENÁ PŘÍČKA DVOJITÁ | 0 | 1464HWa1096157531 | m3 | Celá stěna | Nový | Sklenářské práce | PROSKLENÁ PŘÍČKA PLNÝ PANEL | no | 1464Stě1096158261 | m3 | Stěna | 0 | 0.1 | 0.886 | 0.886 | 0.089 | 0.317 | 0.089 | 0.032 | 2.8 | Pset_WallCommon - AcousticRating: 0; NEMSOK - Object Layer Attributes #1, Kód prvku: SN11.03.0010; Object Layer Attributes #1, Podlaží: 1.NP; Object Layer Attributes #1, Funkce (venkovní): Ne; Object Layer Attributes #1, Součinitel prostupu tepla: 0; Object Layer Attributes #1, Vážená stavební neprůzvučnost: 47
PROSKLENÁ PŘÍČKA DVOJITÁ | Půdorys 1.NP | PROSKLENÁ PŘÍČKA PLNÝ PANEL 0.1 m |  | PROSKLENÁ PŘÍČKA DVOJITÁ | 0 | 1464HWa1096157533 | m3 | Celá stěna | Nový | Sklenářské práce | PROSKLENÁ PŘÍČKA PLNÝ PANEL | no | 1464Stě1096158187 | m3 | Stěna | 0 | 0.1 | 0.56 | 0.56 | 0.056 | 0.2 | 0.056 | 0.02 | 2.8 | Pset_WallCommon - AcousticRating: 0; NEMSOK - Object Layer Attributes #1, Kód prvku: SN11.03.0009; Object Layer Attributes #1, Podlaží: 1.NP; Object Layer Attributes #1, Funkce (venkovní): Ne; Object Layer Attributes #1, Součinitel prostupu tepla: 0; Object Layer Attributes #1, Vážená stavební neprůzvučnost: 47
PROSKLENÁ PŘÍČKA DVOJITÁ | Půdorys 1.NP | PROSKLENÁ PŘÍČKA PLNÝ PANEL 0.1 m |  | PROSKLENÁ PŘÍČKA DVOJITÁ | 0 | 1464HWa1096157537 | m3 | Celá stěna | Nový | Sklenářské práce | PROSKLENÁ PŘÍČKA PLNÝ PANEL | no | 1464Stě1096158114 | m3 | Stěna | 0 | 0.1 | 0.56 | 0.56 | 0.056 | 0.2 | 0.056 | 0.02 | 2.8 | Pset_WallCommon - AcousticRating: 0; NEMSOK - Object Layer Attributes #1, Kód prvku: SN11.03.0007; Object Layer Attributes #1, Podlaží: 1.NP; Object Layer Attributes #1, Funkce (venkovní): Ne; Object Layer Attributes #1, Součinitel prostupu tepla: 0; Object Layer Attributes #1, Vážená stavební neprůzvučnost: 47
PROSKLENÁ PŘÍČKA DVOJITÁ | Půdorys 1.NP | PROSKLENÁ PŘÍČKA PLNÝ PANEL 0.1 m |  | PROSKLENÁ PŘÍČKA DVOJITÁ | 0 | 1464HWa1096157541 | m3 | Celá stěna | Nový | Sklenářské práce | PROSKLENÁ PŘÍČKA PLNÝ PANEL | no | 1464Stě1096158140 | m3 | Stěna | 0 | 0.1 | 0.56 | 0.56 | 0.056 | 0.2 | 0.056 | 0.02 | 2.8 | Pset_WallCommon - AcousticRating: 0; NEMSOK - Object Layer Attributes #1, Kód prvku: SN11.03.0008; Object Layer Attributes #1, Podlaží: 1.NP; Object Layer Attributes #1, Funkce (venkovní): Ne; Object Layer Attributes #1, Součinitel prostupu tepla: 0; Object Layer Attributes #1, Vážená stavební neprůzvučnost: 47
PROSKLENÁ PŘÍČKA DVOJITÁ | Půdorys 1.NP | PROSKLENÁ PŘÍČKA DVOJITÁ 0.1 m |  | PROSKLENÁ PŘÍČKA DVOJITÁ | 0 | 1464HWa1096157552 | m3 | Celá stěna | Nový | Sklenářské práce | PROSKLENÁ PŘÍČKA DVOJITÁ | no | 1464Stě1096157559 | m3 | Stěna | 0 | 0.1 | 3.102 | 3.102 | 0.31 | 1.108 | 0.31 | 0.111 | 2.8 | Pset_WallCommon - AcousticRating: 0; NEMSOK - Object Layer Attributes #1, Kód prvku: SN11.03.0004; Object Layer Attributes #1, Podlaží: 1.NP; Object Layer Attributes #1, Funkce (venkovní): Ne; Object Layer Attributes #1, Součinitel prostupu tepla: 0; Object Layer Attributes #1, Vážená stavební neprůzvučnost: 47
PROSKLENÁ PŘÍČKA DVOJITÁ | Půdorys 1.NP | PROSKLENÁ PŘÍČKA PLNÝ PANEL 0.1 m |  | PROSKLENÁ PŘÍČKA DVOJITÁ | 0 | 1464HWa1096157556 | m3 | Celá stěna | Nový | Sklenářské práce | PROSKLENÁ PŘÍČKA PLNÝ PANEL | no | 1464Stě1096158037 | m3 | Stěna | 0 | 0.1 | 0.56 | 0.56 | 0.056 | 0.2 | 0.056 | 0.02 | 2.8 | Pset_WallCommon - AcousticRating: 0; NEMSOK - Object Layer Attributes #1, Kód prvku: SN11.03.0005; Object Layer Attributes #1, Podlaží: 1.NP; Object Layer Attributes #1, Funkce (venkovní): Ne; Object Layer Attributes #1, Součinitel prostupu tepla: 0; Object Layer Attributes #1, Vážená stavební neprůzvučnost: 47
PROSKLENÁ PŘÍČKA DVOJITÁ | Půdorys 1.NP | PROSKLENÁ PŘÍČKA DVOJITÁ 0.1 m |  | PROSKLENÁ PŘÍČKA DVOJITÁ | 0 | 1464HWa1096159774 | m3 | Celá stěna | Nový | Sklenářské práce | PROSKLENÁ PŘÍČKA DVOJITÁ | no | 1464Stě1096159798 | m3 | Stěna | 0 | 0.1 | 19.32 | 15.54 | 1.932 | 6.9 | 1.554 | 0.69 | 2.8 | Pset_WallCommon - AcousticRating: 0; NEMSOK - Object Layer Attributes #1, Kód prvku: SN11.03.0012; Object Layer Attributes #1, Podlaží: 1.NP; Object Layer Attributes #1, Funkce (venkovní): Ne; Object Layer Attributes #1, Součinitel prostupu tepla: 0; Object Layer Attributes #1, Vážená stavební neprůzvučnost: 47
PROSKLENÁ PŘÍČKA DVOJITÁ | Půdorys 1.NP | PROSKLENÁ PŘÍČKA DVOJITÁ 0.1 m |  | PROSKLENÁ PŘÍČKA DVOJITÁ | 0 | 1464HWa1096162610 | m3 | Celá stěna | Nový | Sklenářské práce | PROSKLENÁ PŘÍČKA DVOJITÁ | no | 1464Stě1096162629 | m3 | Stěna | 0 | 0.1 | 6.978 | 4.038 | 0.698 | 2.492 | 0.404 | 0.249 | 2.8 | Pset_WallCommon - AcousticRating: 0; NEMSOK - Object Layer Attributes #1, Kód prvku: SN11.03.0013; Object Layer Attributes #1, Podlaží: 1.NP; Object Layer Attributes #1, Funkce (venkovní): Ne; Object Layer Attributes #1, Součinitel prostupu tepla: 0; Object Layer Attributes #1, Vážená stavební neprůzvučnost: 47
PROSKLENÁ PŘÍČKA DVOJITÁ | Půdorys 1.NP | PROSKLENÁ PŘÍČKA DVOJITÁ 0.1 m |  | PROSKLENÁ PŘÍČKA DVOJITÁ | 0 | 1464HWa1096205532 | m3 | Celá stěna | Nový | Sklenářské práce | PROSKLENÁ PŘÍČKA DVOJITÁ | no | 1464Stě1096205534 | m3 | Stěna | 0 | 0.1 | 7.98 | 5.04 | 0.798 | 2.85 | 0.504 | 0.285 | 2.8 | Pset_WallCommon - AcousticRating: 0; NEMSOK - Object Layer Attributes #1, Kód prvku: SN11.03.0014; Object Layer Attributes #1, Podlaží: 1.NP; Object Layer Attributes #1, Funkce (venkovní): Ne; Object Layer Attributes #1, Součinitel prostupu tepla: 0; Object Layer Attributes #1, Vážená stavební neprůzvučnost: 47
PROSKLENÁ PŘÍČKA DVOJITÁ | Půdorys 1.NP | PROSKLENÁ PŘÍČKA DVOJITÁ 0.1 m |  | PROSKLENÁ PŘÍČKA DVOJITÁ | 0 | 1464HWa1096205680 | m3 | Celá stěna | Nový | Sklenářské práce | PROSKLENÁ PŘÍČKA DVOJITÁ | no | 1464Stě1096205681 | m3 | Stěna | 0 | 0.1 | 9.24 | 6.3 | 0.924 | 3.3 | 0.63 | 0.33 | 2.8 | Pset_WallCommon - AcousticRating: 0; NEMSOK - Object Layer Attributes #1, Kód prvku: SN11.03.0015; Object Layer Attributes #1, Podlaží: 1.NP; Object Layer Attributes #1, Funkce (venkovní): Ne; Object Layer Attributes #1, Součinitel prostupu tepla: 0; Object Layer Attributes #1, Vážená stavební neprůzvučnost: 47
PROSKLENÁ PŘÍČKA DVOJITÁ | Půdorys 1.NP | PROSKLENÁ PŘÍČKA DVOJITÁ 0.1 m |  | PROSKLENÁ PŘÍČKA DVOJITÁ | 0 | 1464HWa1096205802 | m3 | Celá stěna | Nový | Sklenářské práce | PROSKLENÁ PŘÍČKA DVOJITÁ | no | 1464Stě1096205803 | m3 | Stěna | 0 | 0.1 | 9.24 | 6.3 | 0.924 | 3.3 | 0.63 | 0.33 | 2.8 | Pset_WallCommon - AcousticRating: 0; NEMSOK - Object Layer Attributes #1, Kód prvku: SN11.03.0016; Object Layer Attributes #1, Podlaží: 1.NP; Object Layer Attributes #1, Funkce (venkovní): Ne; Object Layer Attributes #1, Součinitel prostupu tepla: 0; Object Layer Attributes #1, Vážená stavební neprůzvučnost: 47
PROSKLENÁ PŘÍČKA DVOJITÁ | Půdorys 1.NP | PROSKLENÁ PŘÍČKA DVOJITÁ 0.1 m |  | PROSKLENÁ PŘÍČKA DVOJITÁ | 0 | 1464HWa1096205855 | m3 | Celá stěna | Nový | Sklenářské práce | PROSKLENÁ PŘÍČKA DVOJITÁ | no | 1464Stě1096205856 | m3 | Stěna | 0 | 0.1 | 9.24 | 6.3 | 0.924 | 3.3 | 0.63 | 0.33 | 2.8 | Pset_WallCommon - AcousticRating: 0; NEMSOK - Object Layer Attributes #1, Kód prvku: SN11.03.0017; Object Layer Attributes #1, Podlaží: 1.NP; Object Layer Attributes #1, Funkce (venkovní): Ne; Object Layer Attributes #1, Součinitel prostupu tepla: 0; Object Layer Attributes #1, Vážená stavební neprůzvučnost: 47
PROSKLENÁ PŘÍČKA DVOJITÁ | Půdorys 1.NP | PROSKLENÁ PŘÍČKA DVOJITÁ 0.1 m |  | PROSKLENÁ PŘÍČKA DVOJITÁ | 0 | 1464HWa1096206052 | m3 | Celá stěna | Nový | Sklenářské práce | PROSKLENÁ PŘÍČKA DVOJITÁ | no | 1464Stě1096206053 | m3 | Stěna | 0 | 0.1 | 6.72 | 3.78 | 0.672 | 2.4 | 0.378 | 0.24 | 2.8 | Pset_WallCommon - AcousticRating: 0; NEMSOK - Object Layer Attributes #1, Kód prvku: SN11.03.0018; Object Layer Attributes #1, Podlaží: 1.NP; Object Layer Attributes #1, Funkce (venkovní): Ne; Object Layer Attributes #1, Součinitel prostupu tepla: 0; Object Layer Attributes #1, Vážená stavební neprůzvučnost: 47
PROSKLENÁ PŘÍČKA DVOJITÁ | Půdorys 1.NP | PROSKLENÁ PŘÍČKA PLNÝ PANEL 0.1 m |  | PROSKLENÁ PŘÍČKA DVOJITÁ | 0 | 1464HWa1096207038 | m3 | Celá stěna | Nový | Sklenářské práce | PROSKLENÁ PŘÍČKA PLNÝ PANEL |  | 1464Stě1096207039 | m3 | Stěna | 0 | 0.1 | 1.4 | 1.4 | 0.14 | 0.5 | 0.14 | 0.05 | 2.8 | Pset_WallCommon - AcousticRating: 0; NEMSOK - Object Layer Attributes #1, Kód prvku: SN11.03.0020; Object Layer Attributes #1, Podlaží: 1.NP; Object Layer Attributes #1, Funkce (venkovní): Ne; Object Layer Attributes #1, Součinitel prostupu tepla: 0; Object Layer Attributes #1, Vážená stavební neprůzvučnost: 47
PROSKLENÁ PŘÍČKA DVOJITÁ | Půdorys 1.NP | PROSKLENÁ PŘÍČKA DVOJITÁ 0.1 m |  | PROSKLENÁ PŘÍČKA DVOJITÁ | 0 | 1464HWa1096207156 | m3 | Celá stěna | Nový | Sklenářské práce | PROSKLENÁ PŘÍČKA DVOJITÁ | no | 1464Stě1096207176 | m3 | Stěna | 0 | 0.1 | 8.82 | 6.93 | 0.882 | 3.15 | 0.693 | 0.315 | 2.8 | Pset_WallCommon - AcousticRating: 0; NEMSOK - Object Layer Attributes #1, Kód prvku: SN11.03.0021; Object Layer Attributes #1, Podlaží: 1.NP; Object Layer Attributes #1, Funkce (venkovní): Ne; Object Layer Attributes #1, Součinitel prostupu tepla: 0; Object Layer Attributes #1, Vážená stavební neprůzvučnost: 47
PROSKLENÁ PŘÍČKA DVOJITÁ | Půdorys 1.NP | PROSKLENÁ PŘÍČKA PLNÝ PANEL 0.1 m |  | PROSKLENÁ PŘÍČKA DVOJITÁ | 0 | 1464HWa1096207201 | m3 | Celá stěna | Nový | Sklenářské práce | PROSKLENÁ PŘÍČKA PLNÝ PANEL |  | 1464Stě1096207203 | m3 | Stěna | 0 | 0.1 | 1.4 | 1.4 | 0.14 | 0.5 | 0.14 | 0.05 | 2.8 | Pset_WallCommon - AcousticRating: 0; NEMSOK - Object Layer Attributes #1, Kód prvku: SN11.03.0022; Object Layer Attributes #1, Podlaží: 1.NP; Object Layer Attributes #1, Funkce (venkovní): Ne; Object Layer Attributes #1, Součinitel prostupu tepla: 0; Object Layer Attributes #1, Vážená stavební neprůzvučnost: 47
PROSKLENÁ PŘÍČKA DVOJITÁ | Půdorys 1.NP | PROSKLENÁ PŘÍČKA DVOJITÁ 0.1 m |  | PROSKLENÁ PŘÍČKA DVOJITÁ | 0 | 1464HWa1096207237 | m3 | Celá stěna | Nový | Sklenářské práce | PROSKLENÁ PŘÍČKA DVOJITÁ | no | 1464Stě1096207257 | m3 | Stěna | 0 | 0.1 | 8.82 | 6.93 | 0.882 | 3.15 | 0.693 | 0.315 | 2.8 | Pset_WallCommon - AcousticRating: 0; NEMSOK - Object Layer Attributes #1, Kód prvku: SN11.03.0023; Object Layer Attributes #1, Podlaží: 1.NP; Object Layer Attributes #1, Funkce (venkovní): Ne; Object Layer Attributes #1, Součinitel prostupu tepla: 0; Object Layer Attributes #1, Vážená stavební neprůzvučnost: 47
PROSKLENÁ PŘÍČKA DVOJITÁ | Půdorys 1.NP | PROSKLENÁ PŘÍČKA PLNÝ PANEL 0.1 m |  | PROSKLENÁ PŘÍČKA DVOJITÁ | 0 | 1464HWa1096207281 | m3 | Celá stěna | Nový | Sklenářské práce | PROSKLENÁ PŘÍČKA PLNÝ PANEL |  | 1464Stě1096207283 | m3 | Stěna | 0 | 0.1 | 1.4 | 1.4 | 0.14 | 0.5 | 0.14 | 0.05 | 2.8 | Pset_WallCommon - AcousticRating: 0; NEMSOK - Object Layer Attributes #1, Kód prvku: SN11.03.0024; Object Layer Attributes #1, Podlaží: 1.NP; Object Layer Attributes #1, Funkce (venkovní): Ne; Object Layer Attributes #1, Součinitel prostupu tepla: 0; Object Layer Attributes #1, Vážená stavební neprůzvučnost: 47
PROSKLENÁ PŘÍČKA DVOJITÁ | Půdorys 1.NP | PROSKLENÁ PŘÍČKA DVOJITÁ 0.1 m |  | PROSKLENÁ PŘÍČKA DVOJITÁ | 0 | 1464HWa1096207319 | m3 | Celá stěna | Nový | Sklenářské práce | PROSKLENÁ PŘÍČKA DVOJITÁ | no | 1464Stě1096207339 | m3 | Stěna | 0 | 0.1 | 8.82 | 6.93 | 0.882 | 3.15 | 0.693 | 0.315 | 2.8 | Pset_WallCommon - AcousticRating: 0; NEMSOK - Object Layer Attributes #1, Kód prvku: SN11.03.0025; Object Layer Attributes #1, Podlaží: 1.NP; Object Layer Attributes #1, Funkce (venkovní): Ne; Object Layer Attributes #1, Součinitel prostupu tepla: 0; Object Layer Attributes #1, Vážená stavební neprůzvučnost: 47
PROSKLENÁ PŘÍČKA DVOJITÁ | Půdorys 1.NP | PROSKLENÁ PŘÍČKA PLNÝ PANEL 0.1 m |  | PROSKLENÁ PŘÍČKA DVOJITÁ | 0 | 1464HWa1096207363 | m3 | Celá stěna | Nový | Sklenářské práce | PROSKLENÁ PŘÍČKA PLNÝ PANEL |  | 1464Stě1096207365 | m3 | Stěna | 0 | 0.1 | 1.4 | 1.4 | 0.14 | 0.5 | 0.14 | 0.05 | 2.8 | Pset_WallCommon - AcousticRating: 0; NEMSOK - Object Layer Attributes #1, Kód prvku: SN11.03.0026; Object Layer Attributes #1, Podlaží: 1.NP; Object Layer Attributes #1, Funkce (venkovní): Ne; Object Layer Attributes #1, Součinitel prostupu tepla: 0; Object Layer Attributes #1, Vážená stavební neprůzvučnost: 47
PROSKLENÁ PŘÍČKA DVOJITÁ | Půdorys 1.NP | PROSKLENÁ PŘÍČKA PLNÝ PANEL 0.1 m |  | PROSKLENÁ PŘÍČKA DVOJITÁ | 0 | 1464HWa1096217781 | m3 | Celá stěna | Nový | Sklenářské práce | PROSKLENÁ PŘÍČKA PLNÝ PANEL | no | 1464Stě1096217783 | m3 | Stěna | 0 | 0.1 | 0.842 | 0.842 | 0.084 | 0.301 | 0.084 | 0.03 | 2.8 | Pset_WallCommon - AcousticRating: 0; NEMSOK - Object Layer Attributes #1, Kód prvku: SN11.03.0027; Object Layer Attributes #1, Podlaží: 1.NP; Object Layer Attributes #1, Funkce (venkovní): Ne; Object Layer Attributes #1, Součinitel prostupu tepla: 0; Object Layer Attributes #1, Vážená stavební neprůzvučnost: 47
PROSKLENÁ PŘÍČKA DVOJITÁ | Půdorys 1.NP | PROSKLENÁ PŘÍČKA PLNÝ PANEL 0.1 m |  | PROSKLENÁ PŘÍČKA DVOJITÁ | 0 | 1464HWa1096217805 | m3 | Celá stěna | Nový | Sklenářské práce | PROSKLENÁ PŘÍČKA PLNÝ PANEL | no | 1464Stě1096217807 | m3 | Stěna | 0 | 0.1 | 0.17 | 0.17 | 0.017 | 0.061 | 0.017 | 0.006 | 2.8 | Pset_WallCommon - AcousticRating: 0; NEMSOK - Object Layer Attributes #1, Kód prvku: SN11.03.0028; Object Layer Attributes #1, Podlaží: 1.NP; Object Layer Attributes #1, Funkce (venkovní): Ne; Object Layer Attributes #1, Součinitel prostupu tepla: 0; Object Layer Attributes #1, Vážená stavební neprůzvučnost: 47
PROSKLENÁ PŘÍČKA DVOJITÁ | Půdorys 1.NP | PROSKLENÁ PŘÍČKA PLNÝ PANEL 0.1 m |  | PROSKLENÁ PŘÍČKA DVOJITÁ | 0 | 1464HWa1096217873 | m3 | Celá stěna | Nový | Sklenářské práce | PROSKLENÁ PŘÍČKA PLNÝ PANEL | no | 1464Stě1096217875 | m3 | Stěna | 0 | 0.1 | 0.17 | 0.17 | 0.017 | 0.061 | 0.017 | 0.006 | 2.8 | Pset_WallCommon - AcousticRating: 0; NEMSOK - Object Layer Attributes #1, Kód prvku: SN11.03.0029; Object Layer Attributes #1, Podlaží: 1.NP; Object Layer Attributes #1, Funkce (venkovní): Ne; Object Layer Attributes #1, Součinitel prostupu tepla: 0; Object Layer Attributes #1, Vážená stavební neprůzvučnost: 47
PROSKLENÁ PŘÍČKA DVOJITÁ | Půdorys 1.NP | PROSKLENÁ PŘÍČKA DVOJITÁ 0.1 m |  | PROSKLENÁ PŘÍČKA DVOJITÁ | 0 | 1464HWa1096206994 | m3 | Celá stěna | Nový | Sklenářské práce | PROSKLENÁ PŘÍČKA DVOJITÁ | no | 1464Stě1096207013 | m3 | Stěna | 0 | 0.1 | 8.82 | 6.93 | 0.882 | 3.15 | 0.693 | 0.315 | 2.8 | Pset_WallCommon - AcousticRating: 0; NEMSOK - Object Layer Attributes #1, Kód prvku: SN11.03.0019; Object Layer Attributes #1, Podlaží: 1.NP; Object Layer Attributes #1, Funkce (venkovní): Ne; Object Layer Attributes #1, Součinitel prostupu tepla: 0; Object Layer Attributes #1, Vážená stavební neprůzvučnost: 47
STÁVAJÍCÍ KCE | Půdorys 1.NP | STÁVAJÍC KCE 0.4 m |  | STÁVAJÍCÍ KCE | REI 180 | 1464HWa1096325899 | m3 | Celá stěna | Stávající | Zednické práce | STÁVAJÍC KCE |  | 1464Stě1096325901 | m3 | Stěna | 0.541 | 0.4 | 5.13 | 0 | 2.052 | 1.8 | 0 | 0.72 | 2.85 | Pset_WallCommon - AcousticRating: 48 dB
PROSKLENÁ PŘÍČKA JEDNODUCHÁ | Půdorys 1.NP | PROSKLENÁ FASÁDA 0.055 m |  | PROSKLENÁ PŘÍČKA JEDNODUCHÁ | bez požadavku | 1464HWa1096158504 | m3 | Celá stěna | Nový | Zavěšené fasády | PROSKLENÁ FASÁDA | no | 1464Stě1096158523 | m2 | Stěna | 0.7 | 0.055 | 6.66 | 2.34 | 0.366 | 1.8 | 0.129 | 0.099 | 3.7 | Pset_WallCommon - AcousticRating: 37 dB; NEMSOK - Object Layer Attributes #1, Kód prvku: LP01.02.0002; Object Layer Attributes #1, Funkce (venkovní): Ano
SDK SVISLA CAST PODHLEDU | Půdorys 1.NP | SDK SVISLA CAST PODHLEDU 0.04 m |  | SDK SVISLA CAST PODHLEDU |  | 1464HWa1096312560 | m3 | Celá stěna | Nový | Suché stavební práce | SDK SVISLA CAST PODHLEDU | no | 1464Stě1096312562 | m2 | Stěna |  | 0.04 | 0.895 | 0.895 | 0.036 | 4.475 | 0.036 | 0.179 | 0.2 | NEMSOK - Object Layer Attributes #1, Kód prvku: PH01.03.0001; Object Layer Attributes #1, Požární odolnost: bez požadavku; Object Layer Attributes #1, Statická funkce: Ne; Object Layer Attributes #1, Výška svěšení: 0.8 m; Object Layer Attributes #1, Únosnost bodová: 0.5 kg
SDK SVISLA CAST PODHLEDU | Půdorys 1.NP | SDK SVISLA CAST PODHLEDU 0.04 m |  | SDK SVISLA CAST PODHLEDU |  | 1464HWa1096232404 | m3 | Celá stěna | Nový | Suché stavební práce | SDK SVISLA CAST PODHLEDU | no | 1464Stě1096232405 | m2 | Stěna |  | 0.04 | 0.54 | 0.54 | 0.022 | 2.7 | 0.022 | 0.108 | 0.2 | NEMSOK - Object Layer Attributes #1, Kód prvku: PH01.03.0001; Object Layer Attributes #1, Požární odolnost: bez požadavku; Object Layer Attributes #1, Statická funkce: Ne; Object Layer Attributes #1, Výška svěšení: 0.45 m; Object Layer Attributes #1, Únosnost bodová: 0.5 kg
ZELEZOBETONOVÁ KCE | Půdorys 1.NP | ZELEZOBETONOVÁ KCE 0.2 m, MINERÁLNÍ VATA 0.3 m |  | ZELEZOBETONOVÁ KCE |  | 1464HWa0000000004 | m3 | Celá stěna | Nový | Betonářské práce | ZELEZOBETONOVÁ KCE | yes | 1464Stě0000000335 | m3 | Stěna |  | 0.5 | 19.099 | 19.003 | 8.776 | 5.49 | 8.719 | 2.756 | 3.55 | NEMSOK - Object Layer Attributes #2, 2D interakce: yes; Object Layer Attributes #2, Status: Nový; Object Layer Attributes #2, Práce: Zateplovací systémy; Object Layer Attributes #2, Materiál: MINERÁLNÍ VATA; Object Layer Attributes #2, Allright_Stavebni_dil_ID: 1464Stě0000000339; Object Layer Attributes #2, Jednotka: m3; Object Layer Attributes #2, Název_objektu: Stěna; Object Layer Attributes #2, Staticky nosná konstrukce: no; Object Layer Attributes #1, Kód prvku: SN02.03.0001; Object Layer Attributes #1, Funkce: Ano; Object Layer Attributes #1, U-hodnota: 3.37; Object Layer Attributes #1, Podlaží: 1.NP; Object Layer Attributes #1, Požární odolnost: A; Object Layer Attributes #1, Třída pevnosti ocele: B500B; Object Layer Attributes #1, Stupeň vyztužení: 150; Object Layer Attributes #1, Třída pevnosti betonu: C25/30-XC1; Object Layer Attributes #1, Krytí výztuže: 25mm; Object Layer Attributes #1, Statická funkce: Ano; Object Layer Attributes #2, Kód prvku: TI06.03.0002; Object Layer Attributes #2, Požární odolnost: A1; Object Layer Attributes #2, Součinitel prostupu tepla: 0.036; Object Layer Attributes #2, Součinitel difúzního odporu: 1; Object Layer Attributes #2, Způsob spojení vrstev: Lepený + mechanicky kotvený; Object Layer Attributes #2, Systém kotvení: -
ZELEZOBETONOVÁ KCE | Půdorys 1.NP | ZELEZOBETONOVÁ KCE 0.2 m, MINERÁLNÍ VATA 0.3 m |  | ZELEZOBETONOVÁ KCE |  | 1464HWa0000000006 | m3 | Celá stěna | Nový | Betonářské práce | ZELEZOBETONOVÁ KCE | yes | 1464Stě0000001134 | m3 | Stěna |  | 0.5 | 12.958 | 11.833 | 6.264 | 3.9 | 5.702 | 1.975 | 3.55 | NEMSOK - Object Layer Attributes #2, 2D interakce: yes; Object Layer Attributes #2, Status: Nový; Object Layer Attributes #2, Práce: Zateplovací systémy; Object Layer Attributes #2, Materiál: MINERÁLNÍ VATA; Object Layer Attributes #2, Allright_Stavebni_dil_ID: 1464Stě0000001130; Object Layer Attributes #2, Jednotka: m3; Object Layer Attributes #2, Název_objektu: Stěna; Object Layer Attributes #2, Staticky nosná konstrukce: no; Object Layer Attributes #1, Kód prvku: SN02.03.0005; Object Layer Attributes #1, Funkce: Ano; Object Layer Attributes #1, U-hodnota: 3.37; Object Layer Attributes #1, Podlaží: 1.NP; Object Layer Attributes #1, Požární odolnost: A; Object Layer Attributes #1, Třída pevnosti ocele: B500B; Object Layer Attributes #1, Stupeň vyztužení: 150; Object Layer Attributes #1, Třída pevnosti betonu: C25/30-XC1; Object Layer Attributes #1, Krytí výztuže: 25mm; Object Layer Attributes #1, Statická funkce: Ano; Object Layer Attributes #2, Kód prvku: TI06.03.0005; Object Layer Attributes #2, Požární odolnost: A1; Object Layer Attributes #2, Součinitel prostupu tepla: 0.036; Object Layer Attributes #2, Součinitel difúzního odporu: 1; Object Layer Attributes #2, Způsob spojení vrstev: Lepený + mechanicky kotvený; Object Layer Attributes #2, Systém kotvení: -
ZELEZOBETONOVÁ KCE | Půdorys 1.NP | ZELEZOBETONOVÁ KCE 0.2 m |  | ZELEZOBETONOVÁ KCE |  | 1464HWa0000000091 | m3 | Celá stěna | Nový | Betonářské práce | ZELEZOBETONOVÁ KCE | yes | 1464Stě0000001107 | m3 | Stěna |  | 0.2 | 12.176 | 9.499 | 2.435 | 3.43 | 1.9 | 0.686 | 3.55 | NEMSOK - Object Layer Attributes #1, Kód prvku: SN02.03.0002; Object Layer Attributes #1, Funkce: Ne; Object Layer Attributes #1, U-hodnota: 3.37; Object Layer Attributes #1, Podlaží: 1.NP; Object Layer Attributes #1, Požární odolnost: A; Object Layer Attributes #1, Třída pevnosti ocele: B500B; Object Layer Attributes #1, Stupeň vyztužení: 150; Object Layer Attributes #1, Třída pevnosti betonu: C25/30-XC1; Object Layer Attributes #1, Krytí výztuže: 25mm; Object Layer Attributes #1, Statická funkce: Ano
ZELEZOBETONOVÁ KCE | Půdorys 1.NP | ZELEZOBETONOVÁ KCE 0.2 m |  | ZELEZOBETONOVÁ KCE |  | 1464HWa0000000103 | m3 | Celá stěna | Nový | Betonářské práce | ZELEZOBETONOVÁ KCE | yes | 1464Stě0000002162 | m3 | Stěna |  | 0.2 | 8.023 | 5.948 | 1.605 | 2.26 | 1.19 | 0.452 | 3.55 | NEMSOK - Object Layer Attributes #1, Kód prvku: SN02.03.0007; Object Layer Attributes #1, Funkce: Ne; Object Layer Attributes #1, U-hodnota: 3.37; Object Layer Attributes #1, Podlaží: 1.NP; Object Layer Attributes #1, Požární odolnost: A; Object Layer Attributes #1, Třída pevnosti ocele: B500B; Object Layer Attributes #1, Stupeň vyztužení: 150; Object Layer Attributes #1, Třída pevnosti betonu: C25/30-XC1; Object Layer Attributes #1, Krytí výztuže: 25mm; Object Layer Attributes #1, Statická funkce: Ano
ZELEZOBETONOVÁ KCE | Půdorys 1.NP | ZELEZOBETONOVÁ KCE 0.2 m, MINERÁLNÍ VATA 0.3 m |  | ZELEZOBETONOVÁ KCE |  | 1464HWa0000000346 | m3 | Celá stěna | Nový | Betonářské práce | ZELEZOBETONOVÁ KCE | yes | 1464Stě0000001122 | m3 | Stěna |  | 0.5 | 26.199 | 14.999 | 11.612 | 7.29 | 6.642 | 3.636 | 3.55 | NEMSOK - Object Layer Attributes #2, 2D interakce: yes; Object Layer Attributes #2, Status: Nový; Object Layer Attributes #2, Práce: Zateplovací systémy; Object Layer Attributes #2, Materiál: MINERÁLNÍ VATA; Object Layer Attributes #2, Allright_Stavebni_dil_ID: 1464Stě0000001119; Object Layer Attributes #2, Jednotka: m3; Object Layer Attributes #2, Název_objektu: Stěna; Object Layer Attributes #2, Staticky nosná konstrukce: no; Object Layer Attributes #1, Kód prvku: SN02.03.0003; Object Layer Attributes #1, Funkce: Ano; Object Layer Attributes #1, U-hodnota: 3.37; Object Layer Attributes #1, Podlaží: 1.NP; Object Layer Attributes #1, Požární odolnost: A; Object Layer Attributes #1, Třída pevnosti ocele: B500B; Object Layer Attributes #1, Stupeň vyztužení: 150; Object Layer Attributes #1, Třída pevnosti betonu: C25/30-XC1; Object Layer Attributes #1, Krytí výztuže: 25mm; Object Layer Attributes #1, Statická funkce: Ano; Object Layer Attributes #2, Kód prvku: TI06.03.0003; Object Layer Attributes #2, Požární odolnost: A1; Object Layer Attributes #2, Součinitel prostupu tepla: 0.036; Object Layer Attributes #2, Součinitel difúzního odporu: 1; Object Layer Attributes #2, Způsob spojení vrstev: Lepený + mechanicky kotvený; Object Layer Attributes #2, Systém kotvení: -
ZELEZOBETONOVÁ KCE | Půdorys 1.NP | ZELEZOBETONOVÁ KCE 0.2 m |  | ZELEZOBETONOVÁ KCE |  | 1464HWa0000001081 | m3 | Celá stěna | Nový | Betonářské práce | ZELEZOBETONOVÁ KCE | yes | 1464Stě0000001139 | m3 | Stěna |  | 0.2 | 26.554 | 21.417 | 5.311 | 7.48 | 4.279 | 1.496 | 3.55 | NEMSOK - Object Layer Attributes #1, Kód prvku: SN02.03.0006; Object Layer Attributes #1, Funkce: Ne; Object Layer Attributes #1, U-hodnota: 3.37; Object Layer Attributes #1, Podlaží: 1.NP; Object Layer Attributes #1, Požární odolnost: A; Object Layer Attributes #1, Třída pevnosti ocele: B500B; Object Layer Attributes #1, Stupeň vyztužení: 150; Object Layer Attributes #1, Třída pevnosti betonu: C25/30-XC1; Object Layer Attributes #1, Krytí výztuže: 25mm; Object Layer Attributes #1, Statická funkce: Ano
ZELEZOBETONOVÁ KCE | Půdorys 1.NP | ZELEZOBETONOVÁ KCE |  | ZELEZOBETONOVÁ KCE |  | 1464HWa0000001082 | m3 | Celá stěna | Nový | Betonářské práce | ZELEZOBETONOVÁ KCE | yes | 1464Stě0000001126 | m3 | Stěna |  | 0.5 | 15.443 | 15.798 | 6.85 | 4.3 | 6.85 | 2.145 | 3.55 | NEMSOK - Object Layer Attributes #2, 2D interakce: yes; Object Layer Attributes #2, Status: Nový; Object Layer Attributes #2, Práce: Zateplovací systémy; Object Layer Attributes #2, Materiál: MINERÁLNÍ VATA; Object Layer Attributes #2, Allright_Stavebni_dil_ID: 1464Stě0000001124; Object Layer Attributes #2, Jednotka: m3; Object Layer Attributes #2, Název_objektu: Stěna; Object Layer Attributes #2, Staticky nosná konstrukce: no; Object Layer Attributes #1, Kód prvku: SN02.03.0004; Object Layer Attributes #1, Funkce: Ano; Object Layer Attributes #1, U-hodnota: 3.37; Object Layer Attributes #1, Podlaží: 1.NP; Object Layer Attributes #1, Požární odolnost: A; Object Layer Attributes #1, Třída pevnosti ocele: B500B; Object Layer Attributes #1, Stupeň vyztužení: 150; Object Layer Attributes #1, Třída pevnosti betonu: C25/30-XC1; Object Layer Attributes #1, Krytí výztuže: 25mm; Object Layer Attributes #1, Statická funkce: Ano; Object Layer Attributes #2, Kód prvku: TI06.03.0004; Object Layer Attributes #2, Požární odolnost: A1; Object Layer Attributes #2, Součinitel prostupu tepla: 0.036; Object Layer Attributes #2, Součinitel difúzního odporu: 1; Object Layer Attributes #2, Způsob spojení vrstev: Lepený + mechanicky kotvený; Object Layer Attributes #2, Systém kotvení: -
ZELEZOBETONOVÁ KCE | Půdorys 1.NP | ZELEZOBETONOVÁ KCE 0.2 m |  | ZELEZOBETONOVÁ KCE |  | 1464HWa1096140621 | m3 | Celá stěna | Nový | Betonářské práce | ZELEZOBETONOVÁ KCE | yes | 1464Stě1096140622 | m3 | Stěna |  | 0.2 | 2.929 | 2.929 | 0.586 | 0.825 | 0.586 | 0.165 | 3.55 | NEMSOK - Object Layer Attributes #1, Kód prvku: SN02.03.0009; Object Layer Attributes #1, Funkce: Ne; Object Layer Attributes #1, U-hodnota: 3.37; Object Layer Attributes #1, Podlaží: 1.NP; Object Layer Attributes #1, Požární odolnost: A; Object Layer Attributes #1, Třída pevnosti ocele: B500B; Object Layer Attributes #1, Stupeň vyztužení: 150; Object Layer Attributes #1, Třída pevnosti betonu: C25/30-XC1; Object Layer Attributes #1, Krytí výztuže: 25mm; Object Layer Attributes #1, Statická funkce: Ano
ZELEZOBETONOVÁ KCE | Půdorys 1.NP | ZELEZOBETONOVÁ KCE 0.2 m, EPS 0.25 m |  | ZELEZOBETONOVÁ KCE |  | 1464HWa1096145663 | m3 | Celá stěna | Nový | Betonářské práce | ZELEZOBETONOVÁ KCE | yes | 1464Stě1096145665 | m3 | Stěna |  | 0.45 | 12.603 | 12.603 | 5.657 | 3.54 | 5.657 | 1.593 | 3.55 | NEMSOK - Object Layer Attributes #2, 2D interakce: yes; Object Layer Attributes #2, Status: Nový; Object Layer Attributes #2, Práce: Zateplovací systémy; Object Layer Attributes #2, Materiál: EPS; Object Layer Attributes #2, Allright_Stavebni_dil_ID: 1464Stě1096145666; Object Layer Attributes #2, Jednotka: m3; Object Layer Attributes #2, Název_objektu: Stěna; Object Layer Attributes #2, Staticky nosná konstrukce: no; Object Layer Attributes #1, Kód prvku: SN02.03.0010; Object Layer Attributes #1, Funkce: Ne; Object Layer Attributes #1, U-hodnota: 3.37; Object Layer Attributes #1, Podlaží: 1.NP; Object Layer Attributes #1, Požární odolnost: A; Object Layer Attributes #1, Třída pevnosti ocele: B500B; Object Layer Attributes #1, Stupeň vyztužení: 150; Object Layer Attributes #1, Třída pevnosti betonu: C25/30-XC1; Object Layer Attributes #1, Krytí výztuže: 25mm; Object Layer Attributes #1, Statická funkce: Ano; Object Layer Attributes #2, Kód prvku: TI01.03.0012; Object Layer Attributes #2, Požární odolnost: E; Object Layer Attributes #2, Součinitel prostupu tepla: 0.039; Object Layer Attributes #2, Součinitel difúzního odporu: 20 - 40; Object Layer Attributes #2, Způsob spojení vrstev: Mechanicky kotvený; Object Layer Attributes #2, Systém kotvení: -
ZELEZOBETONOVÁ KCE | Půdorys 1.NP | ZELEZOBETONOVÁ KCE 0.2 m |  | ZELEZOBETONOVÁ KCE |  | 1464HWa1096156932 | m3 | Celá stěna | Nový | Betonářské práce | ZELEZOBETONOVÁ KCE | yes | 1464Stě1096159804 | m3 | Stěna |  | 0.2 | 19.24 | 15.421 | 3.848 | 5.2 | 3.084 | 1.04 | 3.7 | NEMSOK - Object Layer Attributes #1, Kód prvku: SN02.03.0037; Object Layer Attributes #1, Funkce: Ne; Object Layer Attributes #1, U-hodnota: 3.37; Object Layer Attributes #1, Podlaží: 1.NP; Object Layer Attributes #1, Požární odolnost: A; Object Layer Attributes #1, Třída pevnosti ocele: B500B; Object Layer Attributes #1, Stupeň vyztužení: 150; Object Layer Attributes #1, Třída pevnosti betonu: C25/30-XC1; Object Layer Attributes #1, Krytí výztuže: 25mm; Object Layer Attributes #1, Statická funkce: Ano
ZELEZOBETONOVÁ KCE | Půdorys 1.NP | ZELEZOBETONOVÁ KCE 0.2 m |  | ZELEZOBETONOVÁ KCE |  | 1464HWa1096156937 | m3 | Celá stěna | Nový | Betonářské práce | ZELEZOBETONOVÁ KCE | yes | 1464Stě1096158477 | m3 | Stěna |  | 0.2 | 11.005 | 7.206 | 2.201 | 3.1 | 1.441 | 0.62 | 3.55 | NEMSOK - Object Layer Attributes #1, Kód prvku: SN02.03.0019; Object Layer Attributes #1, Funkce: Ne; Object Layer Attributes #1, U-hodnota: 3.37; Object Layer Attributes #1, Podlaží: 1.NP; Object Layer Attributes #1, Požární odolnost: A; Object Layer Attributes #1, Třída pevnosti ocele: B500B; Object Layer Attributes #1, Stupeň vyztužení: 150; Object Layer Attributes #1, Třída pevnosti betonu: C25/30-XC1; Object Layer Attributes #1, Krytí výztuže: 25mm; Object Layer Attributes #1, Statická funkce: Ano
ZELEZOBETONOVÁ KCE | Půdorys 1.NP | ZELEZOBETONOVÁ KCE 0.25 m, MINERÁLNÍ VATA 0.3 m |  | ZELEZOBETONOVÁ KCE |  | 1464HWa1096156939 | m3 | Celá stěna | Nový | Betonářské práce | ZELEZOBETONOVÁ KCE | yes | 1464Stě1096157383 | m3 | Stěna |  | 0.55 | 15.265 | 14.14 | 8.048 | 4.425 | 7.429 | 2.44 | 3.55 | NEMSOK - Object Layer Attributes #2, 2D interakce: yes; Object Layer Attributes #2, Status: Nový; Object Layer Attributes #2, Práce: Zateplovací systémy; Object Layer Attributes #2, Materiál: MINERÁLNÍ VATA; Object Layer Attributes #2, Allright_Stavebni_dil_ID: 1464Stě1096157380; Object Layer Attributes #2, Jednotka: m3; Object Layer Attributes #2, Název_objektu: Stěna; Object Layer Attributes #2, Staticky nosná konstrukce: no; Object Layer Attributes #1, Kód prvku: SN02.03.0012; Object Layer Attributes #1, Funkce: Ano; Object Layer Attributes #1, U-hodnota: 3.05; Object Layer Attributes #1, Podlaží: 1.NP; Object Layer Attributes #1, Požární odolnost: A; Object Layer Attributes #1, Třída pevnosti ocele: B500B; Object Layer Attributes #1, Stupeň vyztužení: 150; Object Layer Attributes #1, Třída pevnosti betonu: C25/30-XC1; Object Layer Attributes #1, Krytí výztuže: 25mm; Object Layer Attributes #1, Statická funkce: Ano; Object Layer Attributes #2, Kód prvku: TI06.03.0007; Object Layer Attributes #2, Požární odolnost: A1; Object Layer Attributes #2, Součinitel prostupu tepla: 0.036; Object Layer Attributes #2, Součinitel difúzního odporu: 1; Object Layer Attributes #2, Způsob spojení vrstev: Lepený + mechanicky kotvený; Object Layer Attributes #2, Systém kotvení: -
ZELEZOBETONOVÁ KCE | Půdorys 1.NP | ZELEZOBETONOVÁ KCE 0.25 m, MINERÁLNÍ VATA 0.3 m |  | ZELEZOBETONOVÁ KCE |  | 1464HWa1096156945 | m3 | Celá stěna | Nový | Betonářské práce | ZELEZOBETONOVÁ KCE | yes | 1464Stě1096157474 | m3 | Stěna |  | 0.55 | 23.785 | 21.535 | 11.333 | 6.7 | 10.096 | 3.685 | 3.55 | NEMSOK - Object Layer Attributes #2, 2D interakce: yes; Object Layer Attributes #2, Status: Nový; Object Layer Attributes #2, Práce: Zateplovací systémy; Object Layer Attributes #2, Materiál: MINERÁLNÍ VATA; Object Layer Attributes #2, Allright_Stavebni_dil_ID: 1464Stě1096157479; Object Layer Attributes #2, Jednotka: m3; Object Layer Attributes #2, Název_objektu: Stěna; Object Layer Attributes #2, Staticky nosná konstrukce: no; Object Layer Attributes #1, Kód prvku: SN02.03.0013; Object Layer Attributes #1, Funkce: Ano; Object Layer Attributes #1, U-hodnota: 3.05; Object Layer Attributes #1, Podlaží: 1.NP; Object Layer Attributes #1, Požární odolnost: A; Object Layer Attributes #1, Třída pevnosti ocele: B500B; Object Layer Attributes #1, Stupeň vyztužení: 150; Object Layer Attributes #1, Třída pevnosti betonu: C25/30-XC1; Object Layer Attributes #1, Krytí výztuže: 25mm; Object Layer Attributes #1, Statická funkce: Ano; Object Layer Attributes #2, Kód prvku: TI06.03.0008; Object Layer Attributes #2, Požární odolnost: A1; Object Layer Attributes #2, Součinitel prostupu tepla: 0.036; Object Layer Attributes #2, Součinitel difúzního odporu: 1; Object Layer Attributes #2, Způsob spojení vrstev: Lepený + mechanicky kotvený; Object Layer Attributes #2, Systém kotvení: -
ZELEZOBETONOVÁ KCE | Půdorys 1.NP | ZELEZOBETONOVÁ KCE 0.25 m, MINERÁLNÍ VATA 0.3 m |  | ZELEZOBETONOVÁ KCE |  | 1464HWa1096156947 | m3 | Celá stěna | Nový | Betonářské práce | ZELEZOBETONOVÁ KCE | yes | 1464Stě1096157961 | m3 | Stěna |  | 0.55 | 55.315 | 50.815 | 26.025 | 15.06 | 23.55 | 8.289 | 3.7 | NEMSOK - Object Layer Attributes #2, 2D interakce: yes; Object Layer Attributes #2, Status: Nový; Object Layer Attributes #2, Práce: Zateplovací systémy; Object Layer Attributes #2, Materiál: MINERÁLNÍ VATA; Object Layer Attributes #2, Allright_Stavebni_dil_ID: 1464Stě1096159674; Object Layer Attributes #2, Jednotka: m3; Object Layer Attributes #2, Název_objektu: Stěna; Object Layer Attributes #2, Staticky nosná konstrukce: no; Object Layer Attributes #1, Kód prvku: SN02.03.0016; Object Layer Attributes #1, Funkce: Ano; Object Layer Attributes #1, U-hodnota: 3.05; Object Layer Attributes #1, Podlaží: 1.NP; Object Layer Attributes #1, Požární odolnost: A; Object Layer Attributes #1, Třída pevnosti ocele: B500B; Object Layer Attributes #1, Stupeň vyztužení: 150; Object Layer Attributes #1, Třída pevnosti betonu: C25/30-XC1; Object Layer Attributes #1, Krytí výztuže: 25mm; Object Layer Attributes #1, Statická funkce: Ano; Object Layer Attributes #2, Kód prvku: TI06.03.0011; Object Layer Attributes #2, Požární odolnost: A1; Object Layer Attributes #2, Součinitel prostupu tepla: 0.036; Object Layer Attributes #2, Součinitel difúzního odporu: 1; Object Layer Attributes #2, Způsob spojení vrstev: Lepený + mechanicky kotvený; Object Layer Attributes #2, Systém kotvení: -
ZELEZOBETONOVÁ KCE | Půdorys 1.NP | ZELEZOBETONOVÁ KCE 0.2 m |  | ZELEZOBETONOVÁ KCE |  | 1464HWa1096156949 | m3 | Celá stěna | Nový | Betonářské práce | ZELEZOBETONOVÁ KCE | yes | 1464Stě1096159638 | m3 | Stěna |  | 0.2 | 16.465 | 16.324 | 3.293 | 4.45 | 3.265 | 0.89 | 3.7 | NEMSOK - Object Layer Attributes #1, Kód prvku: SN02.03.0031; Object Layer Attributes #1, Funkce: Ne; Object Layer Attributes #1, U-hodnota: 3.37; Object Layer Attributes #1, Podlaží: 1.NP; Object Layer Attributes #1, Požární odolnost: A; Object Layer Attributes #1, Třída pevnosti ocele: B500B; Object Layer Attributes #1, Stupeň vyztužení: 150; Object Layer Attributes #1, Třída pevnosti betonu: C25/30-XC1; Object Layer Attributes #1, Krytí výztuže: 25mm; Object Layer Attributes #1, Statická funkce: Ano
ZELEZOBETONOVÁ KCE | Půdorys 1.NP | ZELEZOBETONOVÁ KCE 0.25 m, MINERÁLNÍ VATA 0.3 m |  | ZELEZOBETONOVÁ KCE |  | 1464HWa1096157000 | m3 | Celá stěna | Nový | Betonářské práce | ZELEZOBETONOVÁ KCE | yes | 1464Stě1096159724 | m3 | Stěna |  | 0.55 | 31.191 | 18.476 | 15.638 | 8.43 | 9.328 | 4.636 | 3.7 | NEMSOK - Object Layer Attributes #2, 2D interakce: yes; Object Layer Attributes #2, Status: Nový; Object Layer Attributes #2, Práce: Zateplovací systémy; Object Layer Attributes #2, Materiál: MINERÁLNÍ VATA; Object Layer Attributes #2, Allright_Stavebni_dil_ID: 1464Stě1096159345; Object Layer Attributes #2, Jednotka: m3; Object Layer Attributes #2, Název_objektu: Stěna; Object Layer Attributes #2, Staticky nosná konstrukce: no; Object Layer Attributes #1, Kód prvku: SN02.03.0035; Object Layer Attributes #1, Funkce: Ano; Object Layer Attributes #1, U-hodnota: 3.05; Object Layer Attributes #1, Podlaží: 1.NP; Object Layer Attributes #1, Požární odolnost: A; Object Layer Attributes #1, Třída pevnosti ocele: B500B; Object Layer Attributes #1, Stupeň vyztužení: 150; Object Layer Attributes #1, Třída pevnosti betonu: C25/30-XC1; Object Layer Attributes #1, Krytí výztuže: 25mm; Object Layer Attributes #1, Statická funkce: Ano; Object Layer Attributes #2, Kód prvku: TI06.03.0009; Object Layer Attributes #2, Požární odolnost: A1; Object Layer Attributes #2, Součinitel prostupu tepla: 0.036; Object Layer Attributes #2, Součinitel difúzního odporu: 1; Object Layer Attributes #2, Způsob spojení vrstev: Lepený + mechanicky kotvený; Object Layer Attributes #2, Systém kotvení: -
ZELEZOBETONOVÁ KCE | Půdorys 1.NP | ZELEZOBETONOVÁ KCE 0.25 m |  | ZELEZOBETONOVÁ KCE |  | 1464HWa1096157840 | m3 | Celá stěna | Nový | Betonářské práce | ZELEZOBETONOVÁ KCE | yes | 1464Stě1096157887 | m3 | Stěna |  | 0.25 | 5.365 | 5.365 | 1.341 | 1.45 | 1.341 | 0.362 | 3.7 | NEMSOK - Object Layer Attributes #1, Kód prvku: SN02.03.0015; Object Layer Attributes #1, Funkce: Ne; Object Layer Attributes #1, U-hodnota: 3.05; Object Layer Attributes #1, Podlaží: 1.NP; Object Layer Attributes #1, Požární odolnost: A; Object Layer Attributes #1, Třída pevnosti ocele: B500B; Object Layer Attributes #1, Stupeň vyztužení: 150; Object Layer Attributes #1, Třída pevnosti betonu: C25/30-XC1; Object Layer Attributes #1, Krytí výztuže: 25mm; Object Layer Attributes #1, Statická funkce: Ano
ZELEZOBETONOVÁ KCE | Půdorys 1.NP | ZELEZOBETONOVÁ KCE 0.25 m |  | ZELEZOBETONOVÁ KCE |  | 1464HWa1096157842 | m3 | Celá stěna | Nový | Betonářské práce | ZELEZOBETONOVÁ KCE | yes | 1464Stě1096157988 | m3 | Stěna |  | 0.25 | 4.44 | 4.44 | 1.11 | 1.2 | 1.11 | 0.3 | 3.7 | NEMSOK - Object Layer Attributes #1, Kód prvku: SN02.03.0018; Object Layer Attributes #1, Funkce: Ne; Object Layer Attributes #1, U-hodnota: 3.05; Object Layer Attributes #1, Podlaží: 1.NP; Object Layer Attributes #1, Požární odolnost: A; Object Layer Attributes #1, Třída pevnosti ocele: B500B; Object Layer Attributes #1, Stupeň vyztužení: 150; Object Layer Attributes #1, Třída pevnosti betonu: C25/30-XC1; Object Layer Attributes #1, Krytí výztuže: 25mm; Object Layer Attributes #1, Statická funkce: Ano
ZELEZOBETONOVÁ KCE | Půdorys 1.NP | ZELEZOBETONOVÁ KCE 0.25 m |  | ZELEZOBETONOVÁ KCE |  | 1464HWa1096157844 | m3 | Celá stěna | Nový | Betonářské práce | ZELEZOBETONOVÁ KCE | yes | 1464Stě1096159640 | m3 | Stěna |  | 0.25 | 8.066 | 6.4 | 2.017 | 2.18 | 1.78 | 0.545 | 3.7 | NEMSOK - Object Layer Attributes #1, Kód prvku: SN02.03.0032; Object Layer Attributes #1, Funkce: Ne; Object Layer Attributes #1, U-hodnota: 3.05; Object Layer Attributes #1, Podlaží: 1.NP; Object Layer Attributes #1, Požární odolnost: A; Object Layer Attributes #1, Třída pevnosti ocele: B500B; Object Layer Attributes #1, Stupeň vyztužení: 150; Object Layer Attributes #1, Třída pevnosti betonu: C25/30-XC1; Object Layer Attributes #1, Krytí výztuže: 25mm; Object Layer Attributes #1, Statická funkce: Ano
ZELEZOBETONOVÁ KCE | Půdorys 1.NP | ZELEZOBETONOVÁ KCE 0.25 m |  | ZELEZOBETONOVÁ KCE |  | 1464HWa1096157847 | m3 | Celá stěna | Nový | Betonářské práce | ZELEZOBETONOVÁ KCE | yes | 1464Stě1096157853 | m3 | Stěna |  | 0.25 | 4.995 | 4.995 | 1.249 | 1.35 | 1.249 | 0.338 | 3.7 | NEMSOK - Object Layer Attributes #1, Kód prvku: SN02.03.0014; Object Layer Attributes #1, Funkce: Ne; Object Layer Attributes #1, U-hodnota: 3.05; Object Layer Attributes #1, Podlaží: 1.NP; Object Layer Attributes #1, Požární odolnost: A; Object Layer Attributes #1, Třída pevnosti ocele: B500B; Object Layer Attributes #1, Stupeň vyztužení: 150; Object Layer Attributes #1, Třída pevnosti betonu: C25/30-XC1; Object Layer Attributes #1, Krytí výztuže: 25mm; Object Layer Attributes #1, Statická funkce: Ano
ZELEZOBETONOVÁ KCE | Půdorys 1.NP | ZELEZOBETONOVÁ KCE 0.25 m |  | ZELEZOBETONOVÁ KCE |  | 1464HWa1096157850 | m3 | Celá stěna | Nový | Betonářské práce | ZELEZOBETONOVÁ KCE | yes | 1464Stě1096157963 | m3 | Stěna |  | 0.25 | 8.399 | 8.399 | 2.1 | 2.27 | 2.1 | 0.567 | 3.7 | NEMSOK - Object Layer Attributes #1, Kód prvku: SN02.03.0017; Object Layer Attributes #1, Funkce: Ne; Object Layer Attributes #1, U-hodnota: 3.05; Object Layer Attributes #1, Podlaží: 1.NP; Object Layer Attributes #1, Požární odolnost: A; Object Layer Attributes #1, Třída pevnosti ocele: B500B; Object Layer Attributes #1, Stupeň vyztužení: 150; Object Layer Attributes #1, Třída pevnosti betonu: C25/30-XC1; Object Layer Attributes #1, Krytí výztuže: 25mm; Object Layer Attributes #1, Statická funkce: Ano
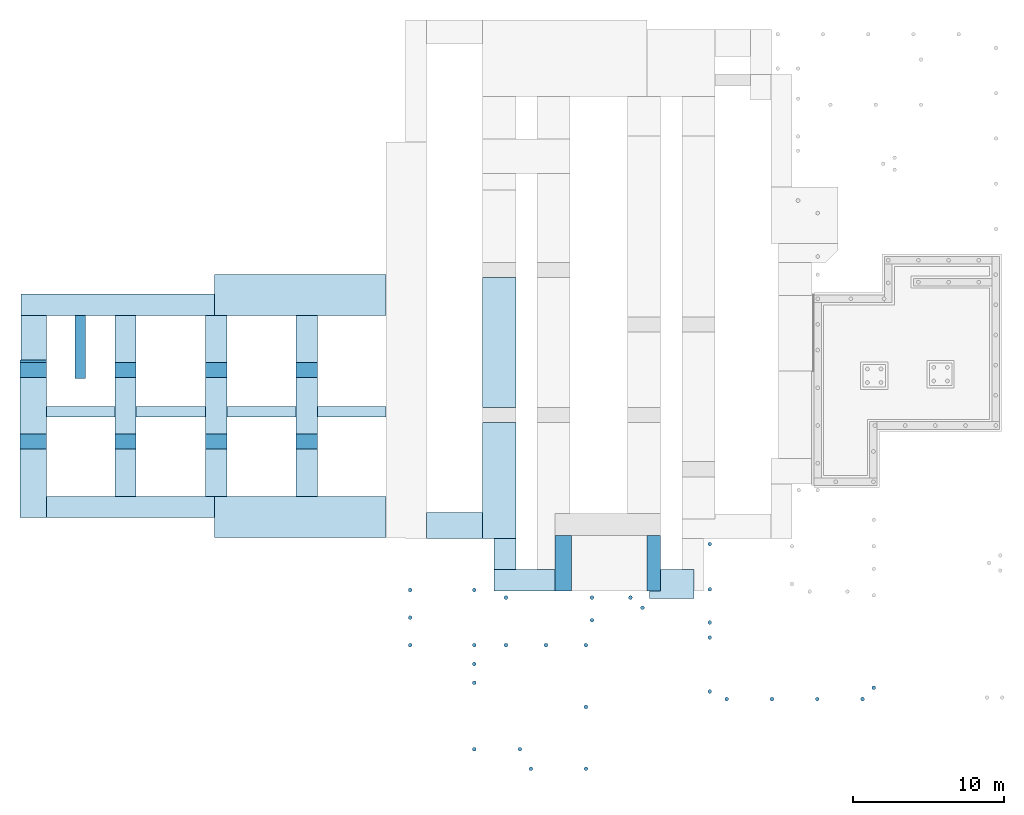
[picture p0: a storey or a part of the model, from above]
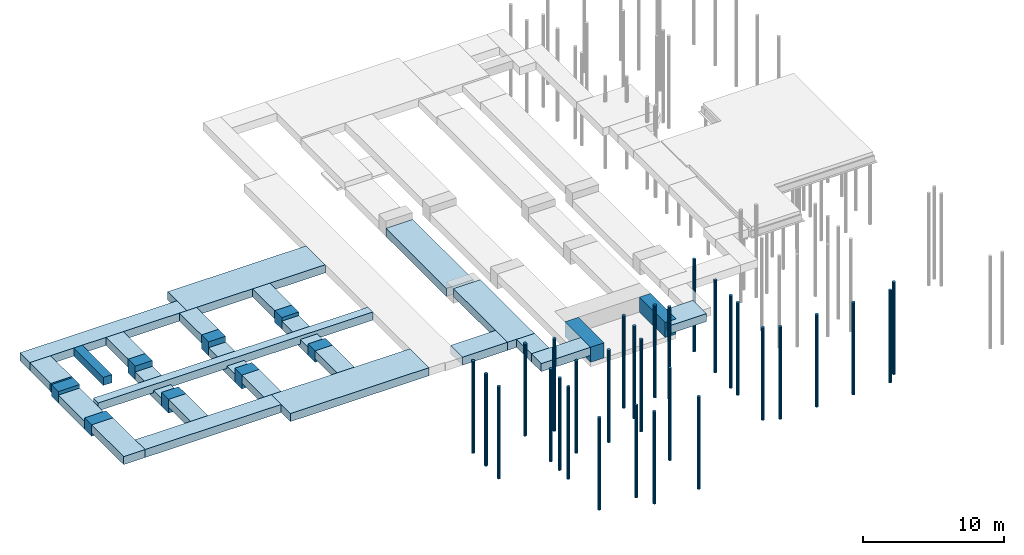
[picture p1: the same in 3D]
Properties of the parts of a building model (IFC4), part 33 of 45

# IfcWall (2385)
Name | In | Material | Faktor | Označení | Požární odolnost | Allright_Stavebni_dil_ID | Jednotka | Název_objektu | Object Layer Attributes #1, Status | Object Layer Attributes #1, Práce | Object Layer Attributes #1, Materiál | Object Layer Attributes #1, Staticky nosná konstrukce | Object Layer Attributes #1, Allright_Stavebni_dil_ID | Object Layer Attributes #1, Jednotka | Object Layer Attributes #1, Název_objektu | ThermalTransmittance (W/K/m2) | Width (m) | GrossSideArea (m2) | NetSideArea (m2) | GrossVolume (m3) | Length (m) | NetVolume (m3) | GrossFootprintArea (m2) | Height (m)
ZELEZOBETONOVÁ KCE | Půdorys 1.NP | ZELEZOBETONOVÁ KCE 0.25 m |  | ZELEZOBETONOVÁ KCE |  | 1464HWa1096157854 | m3 | Celá stěna | Nový | Betonářské práce | ZELEZOBETONOVÁ KCE | yes | 1464Stě1096159542 | m3 | Stěna |  | 0.25 | 1.598 | 1.598 | 0.399 | 0.45 | 0.399 | 0.113 | 3.55 | NEMSOK - Object Layer Attributes #1, Kód prvku: SN02.03.0028; Object Layer Attributes #1, Funkce: Ne; Object Layer Attributes #1, U-hodnota: 3.05; Object Layer Attributes #1, Podlaží: 1.NP; Object Layer Attributes #1, Požární odolnost: A; Object Layer Attributes #1, Třída pevnosti ocele: B500B; Object Layer Attributes #1, Stupeň vyztužení: 150; Object Layer Attributes #1, Třída pevnosti betonu: C25/30-XC1; Object Layer Attributes #1, Krytí výztuže: 25mm; Object Layer Attributes #1, Statická funkce: Ano
ZELEZOBETONOVÁ KCE | Půdorys 1.NP | ZELEZOBETONOVÁ KCE 0.25 m |  | ZELEZOBETONOVÁ KCE |  | 1464HWa1096157856 | m3 | Celá stěna | Nový | Betonářské práce | ZELEZOBETONOVÁ KCE | yes | 1464Stě1096159506 | m3 | Stěna |  | 0.25 | 7.615 | 6.163 | 1.904 | 2.145 | 1.7 | 0.536 | 3.55 | NEMSOK - Object Layer Attributes #1, Kód prvku: SN02.03.0022; Object Layer Attributes #1, Funkce: Ne; Object Layer Attributes #1, U-hodnota: 3.05; Object Layer Attributes #1, Podlaží: 1.NP; Object Layer Attributes #1, Požární odolnost: A; Object Layer Attributes #1, Třída pevnosti ocele: B500B; Object Layer Attributes #1, Stupeň vyztužení: 150; Object Layer Attributes #1, Třída pevnosti betonu: C25/30-XC1; Object Layer Attributes #1, Krytí výztuže: 25mm; Object Layer Attributes #1, Statická funkce: Ano
ZELEZOBETONOVÁ KCE | Půdorys 1.NP | ZELEZOBETONOVÁ KCE 0.2 m |  | ZELEZOBETONOVÁ KCE |  | 1464HWa1096157867 | m3 | Celá stěna | Nový | Betonářské práce | ZELEZOBETONOVÁ KCE | yes | 1464Stě1096159550 | m3 | Stěna |  | 0.2 | 15.904 | 12.476 | 3.181 | 4.48 | 2.495 | 0.896 | 3.55 | NEMSOK - Object Layer Attributes #1, Kód prvku: SN02.03.0029; Object Layer Attributes #1, Funkce: Ne; Object Layer Attributes #1, U-hodnota: 3.37; Object Layer Attributes #1, Podlaží: 1.NP; Object Layer Attributes #1, Požární odolnost: A; Object Layer Attributes #1, Třída pevnosti ocele: B500B; Object Layer Attributes #1, Stupeň vyztužení: 150; Object Layer Attributes #1, Třída pevnosti betonu: C25/30-XC1; Object Layer Attributes #1, Krytí výztuže: 25mm; Object Layer Attributes #1, Statická funkce: Ano
ZELEZOBETONOVÁ KCE | Půdorys 1.NP | ZELEZOBETONOVÁ KCE 0.2 m |  | ZELEZOBETONOVÁ KCE |  | 1464HWa1096157869 | m3 | Celá stěna | Nový | Betonářské práce | ZELEZOBETONOVÁ KCE | yes | 1464Stě1096159518 | m3 | Stěna |  | 0.2 | 13.172 | 13.141 | 2.634 | 3.56 | 2.628 | 0.712 | 3.7 | NEMSOK - Object Layer Attributes #1, Kód prvku: SN02.03.0024; Object Layer Attributes #1, Funkce: Ne; Object Layer Attributes #1, U-hodnota: 3.37; Object Layer Attributes #1, Podlaží: 1.NP; Object Layer Attributes #1, Požární odolnost: A; Object Layer Attributes #1, Třída pevnosti ocele: B500B; Object Layer Attributes #1, Stupeň vyztužení: 150; Object Layer Attributes #1, Třída pevnosti betonu: C25/30-XC1; Object Layer Attributes #1, Krytí výztuže: 25mm; Object Layer Attributes #1, Statická funkce: Ano
ZELEZOBETONOVÁ KCE | Půdorys 1.NP | ZELEZOBETONOVÁ KCE 0.25 m |  | ZELEZOBETONOVÁ KCE |  | 1464HWa1096157871 | m3 | Celá stěna | Nový | Betonářské práce | ZELEZOBETONOVÁ KCE | yes | 1464Stě1096159532 | m3 | Stěna |  | 0.25 | 0.777 | 0.777 | 0.194 | 0.21 | 0.194 | 0.052 | 3.7 | NEMSOK - Object Layer Attributes #1, Kód prvku: SN02.03.0026; Object Layer Attributes #1, Funkce: Ne; Object Layer Attributes #1, U-hodnota: 3.05; Object Layer Attributes #1, Podlaží: 1.NP; Object Layer Attributes #1, Požární odolnost: A; Object Layer Attributes #1, Třída pevnosti ocele: B500B; Object Layer Attributes #1, Stupeň vyztužení: 150; Object Layer Attributes #1, Třída pevnosti betonu: C25/30-XC1; Object Layer Attributes #1, Krytí výztuže: 25mm; Object Layer Attributes #1, Statická funkce: Ano
ZELEZOBETONOVÁ KCE | Půdorys 1.NP | ZELEZOBETONOVÁ KCE 0.2 m |  | ZELEZOBETONOVÁ KCE |  | 1464HWa1096157875 | m3 | Celá stěna | Nový | Betonářské práce | ZELEZOBETONOVÁ KCE | yes | 1464Stě1096159540 | m3 | Stěna |  | 0.2 | 0.746 | 0.746 | 0.149 | 0.21 | 0.149 | 0.042 | 3.55 | NEMSOK - Object Layer Attributes #1, Kód prvku: SN02.03.0027; Object Layer Attributes #1, Funkce: Ne; Object Layer Attributes #1, U-hodnota: 3.37; Object Layer Attributes #1, Podlaží: 1.NP; Object Layer Attributes #1, Požární odolnost: A; Object Layer Attributes #1, Třída pevnosti ocele: B500B; Object Layer Attributes #1, Stupeň vyztužení: 150; Object Layer Attributes #1, Třída pevnosti betonu: C25/30-XC1; Object Layer Attributes #1, Krytí výztuže: 25mm; Object Layer Attributes #1, Statická funkce: Ano
ZELEZOBETONOVÁ KCE | Půdorys 1.NP | ZELEZOBETONOVÁ KCE 0.25 m |  | ZELEZOBETONOVÁ KCE |  | 1464HWa1096157878 | m3 | Celá stěna | Nový | Betonářské práce | ZELEZOBETONOVÁ KCE | yes | 1464Stě1096159480 | m3 | Stěna |  | 0.25 | 5.661 | 5.661 | 1.415 | 1.53 | 1.415 | 0.383 | 3.7 | NEMSOK - Object Layer Attributes #1, Kód prvku: SN02.03.0021; Object Layer Attributes #1, Funkce: Ne; Object Layer Attributes #1, U-hodnota: 3.05; Object Layer Attributes #1, Podlaží: 1.NP; Object Layer Attributes #1, Požární odolnost: A; Object Layer Attributes #1, Třída pevnosti ocele: B500B; Object Layer Attributes #1, Stupeň vyztužení: 150; Object Layer Attributes #1, Třída pevnosti betonu: C25/30-XC1; Object Layer Attributes #1, Krytí výztuže: 25mm; Object Layer Attributes #1, Statická funkce: Ano
ZELEZOBETONOVÁ KCE | Půdorys 1.NP | ZELEZOBETONOVÁ KCE 0.2 m |  | ZELEZOBETONOVÁ KCE |  | 1464HWa1096157880 | m3 | Celá stěna | Nový | Betonářské práce | ZELEZOBETONOVÁ KCE | yes | 1464Stě1096159580 | m3 | Stěna |  | 0.2 | 0.777 | 0.777 | 0.155 | 0.21 | 0.155 | 0.042 | 3.7 | NEMSOK - Object Layer Attributes #1, Kód prvku: SN02.03.0030; Object Layer Attributes #1, Funkce: Ne; Object Layer Attributes #1, U-hodnota: 3.37; Object Layer Attributes #1, Podlaží: 1.NP; Object Layer Attributes #1, Požární odolnost: A; Object Layer Attributes #1, Třída pevnosti ocele: B500B; Object Layer Attributes #1, Stupeň vyztužení: 150; Object Layer Attributes #1, Třída pevnosti betonu: C25/30-XC1; Object Layer Attributes #1, Krytí výztuže: 25mm; Object Layer Attributes #1, Statická funkce: Ano
ZELEZOBETONOVÁ KCE | Půdorys 1.NP | ZELEZOBETONOVÁ KCE 0.25 m |  | ZELEZOBETONOVÁ KCE |  | 1464HWa1096157882 | m3 | Celá stěna | Nový | Betonářské práce | ZELEZOBETONOVÁ KCE | yes | 1464Stě1096159475 | m3 | Stěna |  | 0.25 | 3.219 | 3.219 | 0.805 | 0.87 | 0.805 | 0.218 | 3.7 | NEMSOK - Object Layer Attributes #1, Kód prvku: SN02.03.0020; Object Layer Attributes #1, Funkce: Ne; Object Layer Attributes #1, U-hodnota: 3.05; Object Layer Attributes #1, Podlaží: 1.NP; Object Layer Attributes #1, Požární odolnost: A; Object Layer Attributes #1, Třída pevnosti ocele: B500B; Object Layer Attributes #1, Stupeň vyztužení: 150; Object Layer Attributes #1, Třída pevnosti betonu: C25/30-XC1; Object Layer Attributes #1, Krytí výztuže: 25mm; Object Layer Attributes #1, Statická funkce: Ano
ZELEZOBETONOVÁ KCE | Půdorys 1.NP | ZELEZOBETONOVÁ KCE 0.25 m, MINERÁLNÍ VATA 0.3 m |  | ZELEZOBETONOVÁ KCE |  | 1464HWa1096157889 | m3 | Celá stěna | Nový | Betonářské práce | ZELEZOBETONOVÁ KCE | yes | 1464Stě1096159685 | m3 | Stěna |  | 0.55 | 53.539 | 49.039 | 25.509 | 14.775 | 23.034 | 8.141 | 3.7 | NEMSOK - Object Layer Attributes #2, 2D interakce: yes; Object Layer Attributes #2, Status: Nový; Object Layer Attributes #2, Práce: Zateplovací systémy; Object Layer Attributes #2, Materiál: MINERÁLNÍ VATA; Object Layer Attributes #2, Allright_Stavebni_dil_ID: 1464Stě1096159692; Object Layer Attributes #2, Jednotka: m3; Object Layer Attributes #2, Název_objektu: Stěna; Object Layer Attributes #2, Staticky nosná konstrukce: no; Object Layer Attributes #1, Kód prvku: SN02.03.0034; Object Layer Attributes #1, Funkce: Ano; Object Layer Attributes #1, U-hodnota: 3.05; Object Layer Attributes #1, Podlaží: 1.NP; Object Layer Attributes #1, Požární odolnost: A; Object Layer Attributes #1, Třída pevnosti ocele: B500B; Object Layer Attributes #1, Stupeň vyztužení: 150; Object Layer Attributes #1, Třída pevnosti betonu: C25/30-XC1; Object Layer Attributes #1, Krytí výztuže: 25mm; Object Layer Attributes #1, Statická funkce: Ano; Object Layer Attributes #2, Kód prvku: TI06.03.0012; Object Layer Attributes #2, Požární odolnost: A1; Object Layer Attributes #2, Součinitel prostupu tepla: 0.036; Object Layer Attributes #2, Součinitel difúzního odporu: 1; Object Layer Attributes #2, Způsob spojení vrstev: Lepený + mechanicky kotvený; Object Layer Attributes #2, Systém kotvení: -
ZELEZOBETONOVÁ KCE | Půdorys 1.NP | ZELEZOBETONOVÁ KCE 0.2 m |  | ZELEZOBETONOVÁ KCE |  | 1464HWa1096159502 | m3 | Celá stěna | Nový | Betonářské práce | ZELEZOBETONOVÁ KCE | yes | 1464Stě1096159512 | m3 | Stěna |  | 0.2 | 0.745 | 0.746 | 0.149 | 0.21 | 0.149 | 0.042 | 3.55 | NEMSOK - Object Layer Attributes #1, Kód prvku: SN02.03.0023; Object Layer Attributes #1, Funkce: Ne; Object Layer Attributes #1, U-hodnota: 3.37; Object Layer Attributes #1, Podlaží: 1.NP; Object Layer Attributes #1, Požární odolnost: A; Object Layer Attributes #1, Třída pevnosti ocele: B500B; Object Layer Attributes #1, Stupeň vyztužení: 150; Object Layer Attributes #1, Třída pevnosti betonu: C25/30-XC1; Object Layer Attributes #1, Krytí výztuže: 25mm; Object Layer Attributes #1, Statická funkce: Ano
ZELEZOBETONOVÁ KCE | Půdorys 1.NP | ZELEZOBETONOVÁ KCE 0.25 m |  | ZELEZOBETONOVÁ KCE |  | 1464HWa1096159519 | m3 | Celá stěna | Nový | Betonářské práce | ZELEZOBETONOVÁ KCE | yes | 1464Stě1096159524 | m3 | Stěna |  | 0.25 | 12.802 | 12.802 | 3.201 | 3.46 | 3.201 | 0.865 | 3.7 | NEMSOK - Object Layer Attributes #1, Kód prvku: SN02.03.0025; Object Layer Attributes #1, Funkce: Ne; Object Layer Attributes #1, U-hodnota: 3.05; Object Layer Attributes #1, Podlaží: 1.NP; Object Layer Attributes #1, Požární odolnost: A; Object Layer Attributes #1, Třída pevnosti ocele: B500B; Object Layer Attributes #1, Stupeň vyztužení: 150; Object Layer Attributes #1, Třída pevnosti betonu: C25/30-XC1; Object Layer Attributes #1, Krytí výztuže: 25mm; Object Layer Attributes #1, Statická funkce: Ano
ZELEZOBETONOVÁ KCE | Půdorys 1.NP | ZELEZOBETONOVÁ KCE 0.2 m |  | ZELEZOBETONOVÁ KCE |  | 1464HWa1096159582 | m3 | Celá stěna | Nový | Betonářské práce | ZELEZOBETONOVÁ KCE | yes | 1464Stě1096159668 | m3 | Stěna |  | 0.2 | 31.746 | 24.377 | 6.349 | 8.58 | 4.875 | 1.716 | 3.7 | NEMSOK - Object Layer Attributes #1, Kód prvku: SN02.03.0033; Object Layer Attributes #1, Funkce: Ne; Object Layer Attributes #1, U-hodnota: 3.37; Object Layer Attributes #1, Podlaží: 1.NP; Object Layer Attributes #1, Požární odolnost: A; Object Layer Attributes #1, Třída pevnosti ocele: B500B; Object Layer Attributes #1, Stupeň vyztužení: 150; Object Layer Attributes #1, Třída pevnosti betonu: C25/30-XC1; Object Layer Attributes #1, Krytí výztuže: 25mm; Object Layer Attributes #1, Statická funkce: Ano
ZELEZOBETONOVÁ KCE | Půdorys 1.NP | ZELEZOBETONOVÁ KCE 0.2 m |  | ZELEZOBETONOVÁ KCE |  | 1464HWa1096172091 | m3 | Celá stěna | Nový | Betonářské práce | ZELEZOBETONOVÁ KCE | yes | 1464Stě1096172092 | m3 | Stěna |  | 0.2 | 0.777 | 0.777 | 0.155 | 0.21 | 0.155 | 0.042 | 3.7 | NEMSOK - Object Layer Attributes #1, Kód prvku: SN02.03.0038; Object Layer Attributes #1, Funkce: Ne; Object Layer Attributes #1, U-hodnota: 3.37; Object Layer Attributes #1, Podlaží: 1.NP; Object Layer Attributes #1, Požární odolnost: A; Object Layer Attributes #1, Třída pevnosti ocele: B500B; Object Layer Attributes #1, Stupeň vyztužení: 150; Object Layer Attributes #1, Třída pevnosti betonu: C25/30-XC1; Object Layer Attributes #1, Krytí výztuže: 25mm; Object Layer Attributes #1, Statická funkce: Ano
ZELEZOBETONOVÁ KCE | Půdorys 1.NP | ZELEZOBETONOVÁ KCE 0.25 m, MINERÁLNÍ VATA 0.3 m |  | ZELEZOBETONOVÁ KCE |  | 1464HWa1096174711 | m3 | Celá stěna | Nový | Betonářské práce | ZELEZOBETONOVÁ KCE | yes | 1464Stě1096174712 | m3 | Stěna |  | 0.55 | 8.946 | 8.946 | 4.301 | 2.37 | 4.301 | 1.296 | 3.55 | NEMSOK - Object Layer Attributes #2, 2D interakce: yes; Object Layer Attributes #2, Status: Nový; Object Layer Attributes #2, Práce: Zateplovací systémy; Object Layer Attributes #2, Materiál: MINERÁLNÍ VATA; Object Layer Attributes #2, Allright_Stavebni_dil_ID: 1464Stě1096174713; Object Layer Attributes #2, Jednotka: m3; Object Layer Attributes #2, Název_objektu: Stěna; Object Layer Attributes #2, Staticky nosná konstrukce: no; Object Layer Attributes #1, Kód prvku: SN02.03.0039; Object Layer Attributes #1, Funkce: Ano; Object Layer Attributes #1, U-hodnota: 3.05; Object Layer Attributes #1, Podlaží: 1.NP; Object Layer Attributes #1, Požární odolnost: A; Object Layer Attributes #1, Třída pevnosti ocele: B500B; Object Layer Attributes #1, Stupeň vyztužení: 150; Object Layer Attributes #1, Třída pevnosti betonu: C25/30-XC1; Object Layer Attributes #1, Krytí výztuže: 25mm; Object Layer Attributes #1, Statická funkce: Ano; Object Layer Attributes #2, Kód prvku: TI06.03.0014; Object Layer Attributes #2, Požární odolnost: A1; Object Layer Attributes #2, Součinitel prostupu tepla: 0.036; Object Layer Attributes #2, Součinitel difúzního odporu: 1; Object Layer Attributes #2, Způsob spojení vrstev: Lepený + mechanicky kotvený; Object Layer Attributes #2, Systém kotvení: -
ZELEZOBETONOVÁ KCE | Půdorys 1.NP | ZELEZOBETONOVÁ KCE 0.25 m |  | ZELEZOBETONOVÁ KCE |  | 1464HWa1096175340 | m3 | Celá stěna | Nový | Betonářské práce | ZELEZOBETONOVÁ KCE | yes | 1464Stě1096175341 | m3 | Stěna |  | 0.25 | 1.961 | 1.961 | 0.49 | 0.53 | 0.49 | 0.133 | 3.7 | NEMSOK - Object Layer Attributes #1, Kód prvku: SN02.03.0040; Object Layer Attributes #1, Funkce: Ne; Object Layer Attributes #1, U-hodnota: 3.05; Object Layer Attributes #1, Podlaží: 1.NP; Object Layer Attributes #1, Požární odolnost: A; Object Layer Attributes #1, Třída pevnosti ocele: B500B; Object Layer Attributes #1, Stupeň vyztužení: 150; Object Layer Attributes #1, Třída pevnosti betonu: C25/30-XC1; Object Layer Attributes #1, Krytí výztuže: 25mm; Object Layer Attributes #1, Statická funkce: Ano
ZELEZOBETONOVÁ KCE | Půdorys 1.NP | ZELEZOBETONOVÁ KCE 0.2 m, EPS 0.2 m |  | ZELEZOBETONOVÁ KCE |  | 1464HWa1096140509 | m3 | Celá stěna | Nový | Betonářské práce | ZELEZOBETONOVÁ KCE | yes | 1464Stě1096140510 | m3 | Stěna |  | 0.4 | 2.663 | 2.663 | 1.051 | 0.74 | 1.051 | 0.296 | 3.55 | NEMSOK - Object Layer Attributes #2, 2D interakce: yes; Object Layer Attributes #2, Status: Nový; Object Layer Attributes #2, Práce: Zateplovací systémy; Object Layer Attributes #2, Materiál: EPS; Object Layer Attributes #2, Allright_Stavebni_dil_ID: 1464Stě1096140511; Object Layer Attributes #2, Jednotka: m3; Object Layer Attributes #2, Název_objektu: Stěna; Object Layer Attributes #2, Staticky nosná konstrukce: no; Object Layer Attributes #1, Kód prvku: SN02.03.0008; Object Layer Attributes #1, Funkce: Ne; Object Layer Attributes #1, U-hodnota: 3.37; Object Layer Attributes #1, Podlaží: 1.NP; Object Layer Attributes #1, Požární odolnost: A; Object Layer Attributes #1, Třída pevnosti ocele: B500B; Object Layer Attributes #1, Stupeň vyztužení: 150; Object Layer Attributes #1, Třída pevnosti betonu: C25/30-XC1; Object Layer Attributes #1, Krytí výztuže: 25mm; Object Layer Attributes #1, Statická funkce: Ano; Object Layer Attributes #2, Kód prvku: TI01.03.0008; Object Layer Attributes #2, Požární odolnost: E; Object Layer Attributes #2, Součinitel prostupu tepla: 0.039; Object Layer Attributes #2, Součinitel difúzního odporu: 20 - 40; Object Layer Attributes #2, Způsob spojení vrstev: Mechanicky kotvený; Object Layer Attributes #2, Systém kotvení: -
EPS | Půdorys 1.NP | EPS 0.02 m |  | EPS |  | 1464HWa1096159483 | m3 | Celá stěna | Nový | Zateplovací systémy | EPS | no | 1464Stě1096159488 | m3 | Stěna |  | 0.02 | 0.925 | 0.925 | 0.019 | 0.25 | 0.019 | 0.005 | 3.7 | NEMSOK - Object Layer Attributes #1, Kód prvku: TI01.03.0013; Object Layer Attributes #1, Požární odolnost: E; Object Layer Attributes #1, Systém kotvení: -; Object Layer Attributes #1, Součinitel prostupu tepla: 0.039; Object Layer Attributes #1, Součinitel difúzního odporu: 20 - 40; Object Layer Attributes #1, Způsob spojení vrstev: Mechanicky kotvený
EPS | Půdorys 1.NP | EPS 0.02 m | 1 | EPS |  | 1464HWa1096159507 | m3 | Celá stěna | Nový | Zateplovací systémy | EPS | no | 1464Stě1096159510 | m3 | Stěna |  | 0.02 | 0.74 | 0.74 | 0.015 | 0.2 | 0.015 | 0.004 | 3.7 | NEMSOK - Object Layer Attributes #1, Kód prvku: TI01.03.0014; Object Layer Attributes #1, Požární odolnost: E; Object Layer Attributes #1, Systém kotvení: -; Object Layer Attributes #1, Součinitel prostupu tepla: 0.039; Object Layer Attributes #1, Součinitel difúzního odporu: 20 - 40; Object Layer Attributes #1, Způsob spojení vrstev: Mechanicky kotvený
EPS | Půdorys 1.NP | EPS 0.02 m |  | EPS |  | 1464HWa1096159513 | m3 | Celá stěna | Nový | Zateplovací systémy | EPS | no | 1464Stě1096159516 | m3 | Stěna |  | 0.02 | 0.74 | 0.74 | 0.015 | 0.2 | 0.015 | 0.004 | 3.7 | NEMSOK - Object Layer Attributes #1, Kód prvku: TI01.03.0015; Object Layer Attributes #1, Požární odolnost: E; Object Layer Attributes #1, Systém kotvení: -; Object Layer Attributes #1, Součinitel prostupu tepla: 0.039; Object Layer Attributes #1, Součinitel difúzního odporu: 20 - 40; Object Layer Attributes #1, Způsob spojení vrstev: Mechanicky kotvený
EPS | Půdorys 1.NP | EPS 0.02 m | 1 | EPS |  | 1464HWa1096159521 | m3 | Celá stěna | Nový | Zateplovací systémy | EPS | no | 1464Stě1096159526 | m3 | Stěna |  | 0.02 | 0.925 | 0.925 | 0.019 | 0.25 | 0.019 | 0.005 | 3.7 | NEMSOK - Object Layer Attributes #1, Kód prvku: TI01.03.0016; Object Layer Attributes #1, Požární odolnost: E; Object Layer Attributes #1, Systém kotvení: -; Object Layer Attributes #1, Součinitel prostupu tepla: 0.039; Object Layer Attributes #1, Součinitel difúzního odporu: 20 - 40; Object Layer Attributes #1, Způsob spojení vrstev: Mechanicky kotvený
EPS | Půdorys 1.NP | EPS 0.02 m | 1 | EPS |  | 1464HWa1096159527 | m3 | Celá stěna | Nový | Zateplovací systémy | EPS | no | 1464Stě1096159530 | m3 | Stěna |  | 0.02 | 0.925 | 0.925 | 0.019 | 0.25 | 0.019 | 0.005 | 3.7 | NEMSOK - Object Layer Attributes #1, Kód prvku: TI01.03.0017; Object Layer Attributes #1, Požární odolnost: E; Object Layer Attributes #1, Systém kotvení: -; Object Layer Attributes #1, Součinitel prostupu tepla: 0.039; Object Layer Attributes #1, Součinitel difúzního odporu: 20 - 40; Object Layer Attributes #1, Způsob spojení vrstev: Mechanicky kotvený
EPS | Půdorys 1.NP | EPS 0.02 m |  | EPS |  | 1464HWa1096159535 | m3 | Celá stěna | Nový | Zateplovací systémy | EPS | no | 1464Stě1096159538 | m3 | Stěna |  | 0.02 | 0.74 | 0.74 | 0.015 | 0.2 | 0.015 | 0.004 | 3.7 | NEMSOK - Object Layer Attributes #1, Kód prvku: TI01.03.0018; Object Layer Attributes #1, Požární odolnost: E; Object Layer Attributes #1, Systém kotvení: -; Object Layer Attributes #1, Součinitel prostupu tepla: 0.039; Object Layer Attributes #1, Součinitel difúzního odporu: 20 - 40; Object Layer Attributes #1, Způsob spojení vrstev: Mechanicky kotvený
EPS | Půdorys 1.NP | EPS 0.02 m |  | EPS |  | 1464HWa1096159543 | m3 | Celá stěna | Nový | Zateplovací systémy | EPS | no | 1464Stě1096159546 | m3 | Stěna |  | 0.02 | 0.71 | 0.71 | 0.014 | 0.2 | 0.014 | 0.004 | 3.55 | NEMSOK - Object Layer Attributes #1, Kód prvku: TI01.03.0019; Object Layer Attributes #1, Požární odolnost: E; Object Layer Attributes #1, Systém kotvení: -; Object Layer Attributes #1, Součinitel prostupu tepla: 0.039; Object Layer Attributes #1, Součinitel difúzního odporu: 20 - 40; Object Layer Attributes #1, Způsob spojení vrstev: Mechanicky kotvený
EPS | Půdorys 1.NP | EPS 0.02 m | 1 | EPS |  | 1464HWa1096159551 | m3 | Celá stěna | Nový | Zateplovací systémy | EPS | no | 1464Stě1096159553 | m3 | Stěna |  | 0.02 | 0.444 | 0.444 | 0.009 | 0.125 | 0.009 | 0.003 | 3.55 | NEMSOK - Object Layer Attributes #1, Kód prvku: TI01.03.0020; Object Layer Attributes #1, Požární odolnost: E; Object Layer Attributes #1, Systém kotvení: -; Object Layer Attributes #1, Součinitel prostupu tepla: 0.039; Object Layer Attributes #1, Součinitel difúzního odporu: 20 - 40; Object Layer Attributes #1, Způsob spojení vrstev: Mechanicky kotvený
EPS | Půdorys 1.NP | EPS 0.02 m | 1 | EPS |  | 1464HWa1096159557 | m3 | Celá stěna | Nový | Zateplovací systémy | EPS | no | 1464Stě1096159559 | m3 | Stěna |  | 0.02 | 0.444 | 0.444 | 0.009 | 0.125 | 0.009 | 0.003 | 3.55 | NEMSOK - Object Layer Attributes #1, Kód prvku: TI01.03.0021; Object Layer Attributes #1, Požární odolnost: E; Object Layer Attributes #1, Systém kotvení: -; Object Layer Attributes #1, Součinitel prostupu tepla: 0.039; Object Layer Attributes #1, Součinitel difúzního odporu: 20 - 40; Object Layer Attributes #1, Způsob spojení vrstev: Mechanicky kotvený
EPS | Půdorys 1.NP | EPS | 1 | EPS |  | 1464HWa1096159563 | m3 | Celá stěna | Nový | Zateplovací systémy | EPS | no | 1464Stě1096159565 | m3 | Stěna |  | 0.02 | 0.444 | 0.048 | 0.009 | 0.125 | 0.001 | 0.003 | 3.55 | NEMSOK - Object Layer Attributes #1, Kód prvku: TI01.03.0022; Object Layer Attributes #1, Požární odolnost: E; Object Layer Attributes #1, Systém kotvení: -; Object Layer Attributes #1, Součinitel prostupu tepla: 0.039; Object Layer Attributes #1, Součinitel difúzního odporu: 20 - 40; Object Layer Attributes #1, Způsob spojení vrstev: Mechanicky kotvený
EPS | Půdorys 1.NP | EPS 0.02 m | 1 | EPS |  | 1464HWa1096159569 | m3 | Celá stěna | Nový | Zateplovací systémy | EPS | no | 1464Stě1096159571 | m3 | Stěna |  | 0.02 | 0.444 | 0.444 | 0.009 | 0.125 | 0.009 | 0.003 | 3.55 | NEMSOK - Object Layer Attributes #1, Kód prvku: TI01.03.0023; Object Layer Attributes #1, Požární odolnost: E; Object Layer Attributes #1, Systém kotvení: -; Object Layer Attributes #1, Součinitel prostupu tepla: 0.039; Object Layer Attributes #1, Součinitel difúzního odporu: 20 - 40; Object Layer Attributes #1, Způsob spojení vrstev: Mechanicky kotvený
EPS | Půdorys 1.NP | EPS 0.02 m |  | EPS |  | 1464HWa1096159575 | m3 | Celá stěna | Nový | Zateplovací systémy | EPS | no | 1464Stě1096159578 | m3 | Stěna |  | 0.02 | 0.71 | 0.71 | 0.014 | 0.2 | 0.014 | 0.004 | 3.55 | NEMSOK - Object Layer Attributes #1, Kód prvku: TI01.03.0024; Object Layer Attributes #1, Požární odolnost: E; Object Layer Attributes #1, Systém kotvení: -; Object Layer Attributes #1, Součinitel prostupu tepla: 0.039; Object Layer Attributes #1, Součinitel difúzního odporu: 20 - 40; Object Layer Attributes #1, Způsob spojení vrstev: Mechanicky kotvený
EPS | Půdorys 1.NP | EPS 0.02 m | 1 | EPS |  | 1464HWa1096159659 | m3 | Celá stěna | Nový | Zateplovací systémy | EPS | no | 1464Stě1096159662 | m3 | Stěna |  | 0.02 | 0.74 | 0.74 | 0.015 | 0.2 | 0.015 | 0.004 | 3.7 | NEMSOK - Object Layer Attributes #1, Kód prvku: TI01.03.0025; Object Layer Attributes #1, Požární odolnost: E; Object Layer Attributes #1, Systém kotvení: -; Object Layer Attributes #1, Součinitel prostupu tepla: 0.039; Object Layer Attributes #1, Součinitel difúzního odporu: 20 - 40; Object Layer Attributes #1, Způsob spojení vrstev: Mechanicky kotvený
EPS | Půdorys 1.NP | EPS 0.02 m |  | EPS |  | 1464HWa1096159693 | m3 | Celá stěna | Nový | Zateplovací systémy | EPS | no | 1464Stě1096159696 | m3 | Stěna |  | 0.02 | 0.925 | 0.925 | 0.019 | 0.25 | 0.019 | 0.005 | 3.7 | NEMSOK - Object Layer Attributes #1, Kód prvku: TI01.03.0026; Object Layer Attributes #1, Požární odolnost: E; Object Layer Attributes #1, Systém kotvení: -; Object Layer Attributes #1, Součinitel prostupu tepla: 0.039; Object Layer Attributes #1, Součinitel difúzního odporu: 20 - 40; Object Layer Attributes #1, Způsob spojení vrstev: Mechanicky kotvený
EPS | Půdorys 1.NP | EPS 0.28 m |  | EPS |  | 1464HWa1096164389 | m3 | Celá stěna | Nový | Zateplovací systémy | EPS | no | 1464Stě1096164390 | m3 | Stěna |  | 0.28 | 10.92 | 10.92 | 3.058 | 2.8 | 3.058 | 0.784 | 3.9 | NEMSOK - Object Layer Attributes #1, Kód prvku: TI01.03.0027; Object Layer Attributes #1, Požární odolnost: E; Object Layer Attributes #1, Systém kotvení: -; Object Layer Attributes #1, Součinitel prostupu tepla: 0.039; Object Layer Attributes #1, Součinitel difúzního odporu: 20 - 40; Object Layer Attributes #1, Způsob spojení vrstev: Mechanicky kotvený
EPS | Půdorys 1.NP | EPS 0.28 m | 1 | EPS |  | 1464HWa1096164401 | m3 | Celá stěna | Nový | Zateplovací systémy | EPS | no | 1464Stě1096164402 | m3 | Stěna |  | 0.28 | 5.265 | 5.265 | 1.474 | 1.35 | 1.474 | 0.378 | 3.9 | NEMSOK - Object Layer Attributes #1, Kód prvku: TI01.03.0028; Object Layer Attributes #1, Požární odolnost: E; Object Layer Attributes #1, Systém kotvení: -; Object Layer Attributes #1, Součinitel prostupu tepla: 0.039; Object Layer Attributes #1, Součinitel difúzního odporu: 20 - 40; Object Layer Attributes #1, Způsob spojení vrstev: Mechanicky kotvený
EPS | Půdorys 1.NP | EPS 0.18 m | 1 | EPS |  | 1464HWa1096164422 | m3 | Celá stěna | Nový | Zateplovací systémy | EPS | no | 1464Stě1096164423 | m3 | Stěna |  | 0.18 | 3.705 | 3.697 | 0.667 | 0.95 | 0.665 | 0.171 | 3.9 | NEMSOK - Object Layer Attributes #1, Kód prvku: TI01.03.0029; Object Layer Attributes #1, Požární odolnost: E; Object Layer Attributes #1, Systém kotvení: -; Object Layer Attributes #1, Součinitel prostupu tepla: 0.039; Object Layer Attributes #1, Součinitel difúzního odporu: 20 - 40; Object Layer Attributes #1, Způsob spojení vrstev: Mechanicky kotvený
EPS | Půdorys 1.NP | EPS 0.23 m | 1 | EPS |  | 1464HWa1096164436 | m3 | Celá stěna | Nový | Zateplovací systémy | EPS | no | 1464Stě1096164437 | m3 | Stěna |  | 0.23 | 3.705 | 3.68 | 0.852 | 0.95 | 0.846 | 0.219 | 3.9 | NEMSOK - Object Layer Attributes #1, Kód prvku: TI01.03.0030; Object Layer Attributes #1, Požární odolnost: E; Object Layer Attributes #1, Systém kotvení: -; Object Layer Attributes #1, Součinitel prostupu tepla: 0.039; Object Layer Attributes #1, Součinitel difúzního odporu: 20 - 40; Object Layer Attributes #1, Způsob spojení vrstev: Mechanicky kotvený
EPS | Půdorys 1.NP | EPS 0.23 m | 1 | EPS |  | 1464HWa1096164451 | m3 | Celá stěna | Nový | Zateplovací systémy | EPS | no | 1464Stě1096164452 | m3 | Stěna |  | 0.23 | 3.9 | 3.9 | 0.897 | 1 | 0.897 | 0.23 | 3.9 | NEMSOK - Object Layer Attributes #1, Kód prvku: TI01.03.0031; Object Layer Attributes #1, Požární odolnost: E; Object Layer Attributes #1, Systém kotvení: -; Object Layer Attributes #1, Součinitel prostupu tepla: 0.039; Object Layer Attributes #1, Součinitel difúzního odporu: 20 - 40; Object Layer Attributes #1, Způsob spojení vrstev: Mechanicky kotvený
EPS | Půdorys 1.NP | EPS 0.23 m | 1 | EPS |  | 1464HWa1096164459 | m3 | Celá stěna | Nový | Zateplovací systémy | EPS | no | 1464Stě1096164460 | m3 | Stěna |  | 0.23 | 6.552 | 6.552 | 1.507 | 1.68 | 1.507 | 0.386 | 3.9 | NEMSOK - Object Layer Attributes #1, Kód prvku: TI01.03.0032; Object Layer Attributes #1, Požární odolnost: E; Object Layer Attributes #1, Systém kotvení: -; Object Layer Attributes #1, Součinitel prostupu tepla: 0.039; Object Layer Attributes #1, Součinitel difúzního odporu: 20 - 40; Object Layer Attributes #1, Způsob spojení vrstev: Mechanicky kotvený
EPS | Půdorys 1.NP | EPS 0.23 m | 1 | EPS |  | 1464HWa1096164467 | m3 | Celá stěna | Nový | Zateplovací systémy | EPS | no | 1464Stě1096164468 | m3 | Stěna |  | 0.23 | 3.588 | 3.588 | 0.825 | 0.92 | 0.825 | 0.212 | 3.9 | NEMSOK - Object Layer Attributes #1, Kód prvku: TI01.03.0033; Object Layer Attributes #1, Požární odolnost: E; Object Layer Attributes #1, Systém kotvení: -; Object Layer Attributes #1, Součinitel prostupu tepla: 0.039; Object Layer Attributes #1, Součinitel difúzního odporu: 20 - 40; Object Layer Attributes #1, Způsob spojení vrstev: Mechanicky kotvený
EPS | Půdorys 1.NP | EPS 0.23 m | 1 | EPS |  | 1464HWa1096164484 | m3 | Celá stěna | Nový | Zateplovací systémy | EPS | no | 1464Stě1096164485 | m3 | Stěna |  | 0.23 | 0.925 | 0.925 | 0.213 | 0.25 | 0.213 | 0.058 | 3.7 | NEMSOK - Object Layer Attributes #1, Kód prvku: TI01.03.0034; Object Layer Attributes #1, Požární odolnost: E; Object Layer Attributes #1, Systém kotvení: -; Object Layer Attributes #1, Součinitel prostupu tepla: 0.039; Object Layer Attributes #1, Součinitel difúzního odporu: 20 - 40; Object Layer Attributes #1, Způsob spojení vrstev: Mechanicky kotvený
EPS | Půdorys 1.NP | EPS 0.23 m | 1 | EPS |  | 1464HWa1096164496 | m3 | Celá stěna | Nový | Zateplovací systémy | EPS | no | 1464Stě1096164497 | m3 | Stěna |  | 0.23 | 3.607 | 3.608 | 0.83 | 0.975 | 0.83 | 0.224 | 3.7 | NEMSOK - Object Layer Attributes #1, Kód prvku: TI01.03.0035; Object Layer Attributes #1, Požární odolnost: E; Object Layer Attributes #1, Systém kotvení: -; Object Layer Attributes #1, Součinitel prostupu tepla: 0.039; Object Layer Attributes #1, Součinitel difúzního odporu: 20 - 40; Object Layer Attributes #1, Způsob spojení vrstev: Mechanicky kotvený
EPS | Půdorys 1.NP | EPS 0.18 m | 1 | EPS |  | 1464HWa1096164508 | m3 | Celá stěna | Nový | Zateplovací systémy | EPS | no | 1464Stě1096164509 | m3 | Stěna |  | 0.18 | 4.625 | 4.625 | 0.832 | 1.25 | 0.832 | 0.225 | 3.7 | NEMSOK - Object Layer Attributes #1, Kód prvku: TI01.03.0036; Object Layer Attributes #1, Požární odolnost: E; Object Layer Attributes #1, Systém kotvení: -; Object Layer Attributes #1, Součinitel prostupu tepla: 0.039; Object Layer Attributes #1, Součinitel difúzního odporu: 20 - 40; Object Layer Attributes #1, Způsob spojení vrstev: Mechanicky kotvený
EPS | Půdorys 1.NP | EPS 0.23 m | 1 | EPS |  | 1464HWa1096164521 | m3 | Celá stěna | Nový | Zateplovací systémy | EPS | no | 1464Stě1096164522 | m3 | Stěna |  | 0.23 | 4.995 | 4.995 | 1.149 | 1.35 | 1.149 | 0.31 | 3.7 | NEMSOK - Object Layer Attributes #1, Kód prvku: TI01.03.0037; Object Layer Attributes #1, Požární odolnost: E; Object Layer Attributes #1, Systém kotvení: -; Object Layer Attributes #1, Součinitel prostupu tepla: 0.039; Object Layer Attributes #1, Součinitel difúzního odporu: 20 - 40; Object Layer Attributes #1, Způsob spojení vrstev: Mechanicky kotvený
EPS | Půdorys 1.NP | EPS 0.23 m | 1 | EPS |  | 1464HWa1096164535 | m3 | Celá stěna | Nový | Zateplovací systémy | EPS | no | 1464Stě1096164536 | m3 | Stěna |  | 0.23 | 11.951 | 11.951 | 2.749 | 3.23 | 2.749 | 0.743 | 3.7 | NEMSOK - Object Layer Attributes #1, Kód prvku: TI01.03.0038; Object Layer Attributes #1, Požární odolnost: E; Object Layer Attributes #1, Systém kotvení: -; Object Layer Attributes #1, Součinitel prostupu tepla: 0.039; Object Layer Attributes #1, Součinitel difúzního odporu: 20 - 40; Object Layer Attributes #1, Způsob spojení vrstev: Mechanicky kotvený
EPS | Půdorys 1.NP | EPS 0.02 m | 1 | EPS |  | 1464HWa1096172102 | m3 | Celá stěna | Nový | Zateplovací systémy | EPS | no | 1464Stě1096172104 | m3 | Stěna |  | 0.02 | 0.74 | 0.74 | 0.015 | 0.2 | 0.015 | 0.004 | 3.7 | NEMSOK - Object Layer Attributes #1, Kód prvku: TI01.03.0039; Object Layer Attributes #1, Požární odolnost: E; Object Layer Attributes #1, Systém kotvení: -; Object Layer Attributes #1, Součinitel prostupu tepla: 0.039; Object Layer Attributes #1, Součinitel difúzního odporu: 20 - 40; Object Layer Attributes #1, Způsob spojení vrstev: Mechanicky kotvený
PERIMETR | Půdorys 1.NP | PERIMETR 0.22 m |  | PERIMETR |  | 1464HWa1096195748 | m3 | Celá stěna | Nový | Zateplovací systémy | PERIMETR | no | 1464Stě1096195749 | m3 | Stěna |  | 0.22 | 26.413 | 26.313 | 5.811 | 21.65 | 5.789 | 4.763 | 1.22 | NEMSOK - Object Layer Attributes #1, Kód prvku: TI02.03.0001; Object Layer Attributes #1, Požární odolnost: E; Object Layer Attributes #1, Systém kotvení: -; Object Layer Attributes #1, Součinitel prostupu tepla: 0.034; Object Layer Attributes #1, Součinitel difúzního odporu: 40 - 100; Object Layer Attributes #1, Způsob spojení vrstev: Lepený
PERIMETR | Půdorys 1.NP | PERIMETR 0.22 m | 1 | PERIMETR |  | 1464HWa1096195850 | m3 | Celá stěna | Nový | Zateplovací systémy | PERIMETR | no | 1464Stě1096195851 | m3 | Stěna |  | 0.22 | 18.3 | 18.3 | 4.026 | 15 | 4.026 | 3.3 | 1.22 | NEMSOK - Object Layer Attributes #1, Kód prvku: TI02.03.0002; Object Layer Attributes #1, Požární odolnost: E; Object Layer Attributes #1, Systém kotvení: -; Object Layer Attributes #1, Součinitel prostupu tepla: 0.034; Object Layer Attributes #1, Součinitel difúzního odporu: 40 - 100; Object Layer Attributes #1, Způsob spojení vrstev: Lepený
PERIMETR | Půdorys 1.NP | PERIMETR 0.22 m |  | PERIMETR |  | 1464HWa1096195872 | m3 | Celá stěna | Nový | Zateplovací systémy | PERIMETR | no | 1464Stě1096195873 | m3 | Stěna |  | 0.22 | 9.08 | 9.08 | 1.998 | 11.35 | 1.998 | 2.497 | 0.8 | NEMSOK - Object Layer Attributes #1, Kód prvku: TI02.03.0003; Object Layer Attributes #1, Požární odolnost: E; Object Layer Attributes #1, Systém kotvení: -; Object Layer Attributes #1, Součinitel prostupu tepla: 0.034; Object Layer Attributes #1, Součinitel difúzního odporu: 40 - 100; Object Layer Attributes #1, Způsob spojení vrstev: Lepený
PERIMETR | Půdorys 1.NP | PERIMETR 0.22 m | 1 | PERIMETR |  | 1464HWa1096195922 | m3 | Celá stěna | Nový | Zateplovací systémy | PERIMETR | no | 1464Stě1096195923 | m3 | Stěna |  | 0.22 | 0.376 | 0.376 | 0.083 | 0.47 | 0.083 | 0.103 | 0.8 | NEMSOK - Object Layer Attributes #1, Kód prvku: TI02.03.0004; Object Layer Attributes #1, Požární odolnost: E; Object Layer Attributes #1, Systém kotvení: -; Object Layer Attributes #1, Součinitel prostupu tepla: 0.034; Object Layer Attributes #1, Součinitel difúzního odporu: 40 - 100; Object Layer Attributes #1, Způsob spojení vrstev: Lepený
PERIMETR | Půdorys 1.NP | PERIMETR 0.22 m | 1 | PERIMETR |  | 1464HWa1096195975 | m3 | Celá stěna | Nový | Zateplovací systémy | PERIMETR | no | 1464Stě1096195976 | m3 | Stěna |  | 0.22 | 1.025 | 0.98 | 0.226 | 2.05 | 0.217 | 0.451 | 0.5 | NEMSOK - Object Layer Attributes #1, Kód prvku: TI02.03.0005; Object Layer Attributes #1, Požární odolnost: E; Object Layer Attributes #1, Systém kotvení: -; Object Layer Attributes #1, Součinitel prostupu tepla: 0.034; Object Layer Attributes #1, Součinitel difúzního odporu: 40 - 100; Object Layer Attributes #1, Způsob spojení vrstev: Lepený
PERIMETR | Půdorys 1.NP | PERIMETR 0.22 m | 1 | PERIMETR |  | 1464HWa1096195983 | m3 | Celá stěna | Nový | Zateplovací systémy | PERIMETR | no | 1464Stě1096195984 | m3 | Stěna |  | 0.22 | 1.525 | 1.465 | 0.335 | 3.05 | 0.324 | 0.671 | 0.5 | NEMSOK - Object Layer Attributes #1, Kód prvku: TI02.03.0006; Object Layer Attributes #1, Požární odolnost: E; Object Layer Attributes #1, Systém kotvení: -; Object Layer Attributes #1, Součinitel prostupu tepla: 0.034; Object Layer Attributes #1, Součinitel difúzního odporu: 40 - 100; Object Layer Attributes #1, Způsob spojení vrstev: Lepený
PERIMETR | Půdorys 1.NP | PERIMETR 0.22 m | 1 | PERIMETR |  | 1464HWa1096196024 | m3 | Celá stěna | Nový | Zateplovací systémy | PERIMETR | no | 1464Stě1096196025 | m3 | Stěna |  | 0.22 | 3.704 | 3.704 | 0.815 | 4.63 | 0.815 | 1.019 | 0.8 | NEMSOK - Object Layer Attributes #1, Kód prvku: TI02.03.0007; Object Layer Attributes #1, Požární odolnost: E; Object Layer Attributes #1, Systém kotvení: -; Object Layer Attributes #1, Součinitel prostupu tepla: 0.034; Object Layer Attributes #1, Součinitel difúzního odporu: 40 - 100; Object Layer Attributes #1, Způsob spojení vrstev: Lepený
PERIMETR | Půdorys 1.NP | PERIMETR 0.22 m |  | PERIMETR |  | 1464HWa1096196030 | m3 | Celá stěna | Nový | Zateplovací systémy | PERIMETR | no | 1464Stě1096196031 | m3 | Stěna |  | 0.22 | 1.462 | 1.462 | 0.322 | 2.52 | 0.322 | 0.554 | 0.58 | NEMSOK - Object Layer Attributes #1, Kód prvku: TI02.03.0008; Object Layer Attributes #1, Požární odolnost: E; Object Layer Attributes #1, Systém kotvení: -; Object Layer Attributes #1, Součinitel prostupu tepla: 0.034; Object Layer Attributes #1, Součinitel difúzního odporu: 40 - 100; Object Layer Attributes #1, Způsob spojení vrstev: Lepený
PERIMETR | Půdorys 1.NP | PERIMETR 0.22 m |  | PERIMETR |  | 1464HWa1096196036 | m3 | Celá stěna | Nový | Zateplovací systémy | PERIMETR | no | 1464Stě1096196037 | m3 | Stěna |  | 0.22 | 6.48 | 6.48 | 1.426 | 8.1 | 1.426 | 1.782 | 0.8 | NEMSOK - Object Layer Attributes #1, Kód prvku: TI02.03.0009; Object Layer Attributes #1, Požární odolnost: E; Object Layer Attributes #1, Systém kotvení: -; Object Layer Attributes #1, Součinitel prostupu tepla: 0.034; Object Layer Attributes #1, Součinitel difúzního odporu: 40 - 100; Object Layer Attributes #1, Způsob spojení vrstev: Lepený
PERIMETR | Půdorys 1.NP | PERIMETR 0.22 m | 1 | PERIMETR |  | 1464HWa1096196219 | m3 | Celá stěna | Nový | Zateplovací systémy | PERIMETR | no | 1464Stě1096196221 | m3 | Stěna |  | 0.22 | 3.64 | 3.54 | 0.801 | 4.55 | 0.779 | 1.001 | 0.8 | NEMSOK - Object Layer Attributes #1, Kód prvku: TI02.03.0010; Object Layer Attributes #1, Požární odolnost: E; Object Layer Attributes #1, Systém kotvení: -; Object Layer Attributes #1, Součinitel prostupu tepla: 0.034; Object Layer Attributes #1, Součinitel difúzního odporu: 40 - 100; Object Layer Attributes #1, Způsob spojení vrstev: Lepený
PERIMETR | Půdorys 1.NP | PERIMETR 0.22 m | 1 | PERIMETR |  | 1464HWa1096196310 | m3 | Celá stěna | Nový | Zateplovací systémy | PERIMETR | no | 1464Stě1096196311 | m3 | Stěna |  | 0.22 | 0.56 | 0.52 | 0.123 | 0.7 | 0.114 | 0.154 | 0.8 | NEMSOK - Object Layer Attributes #1, Kód prvku: TI02.03.0011; Object Layer Attributes #1, Požární odolnost: E; Object Layer Attributes #1, Systém kotvení: -; Object Layer Attributes #1, Součinitel prostupu tepla: 0.034; Object Layer Attributes #1, Součinitel difúzního odporu: 40 - 100; Object Layer Attributes #1, Způsob spojení vrstev: Lepený
PERIMETR | Půdorys 1.NP | PERIMETR 0.22 m | 1 | PERIMETR |  | 1464HWa1096196316 | m3 | Celá stěna | Nový | Zateplovací systémy | PERIMETR | no | 1464Stě1096196317 | m3 | Stěna |  | 0.22 | 2.44 | 2.44 | 0.537 | 3.05 | 0.537 | 0.671 | 0.8 | NEMSOK - Object Layer Attributes #1, Kód prvku: TI02.03.0012; Object Layer Attributes #1, Požární odolnost: E; Object Layer Attributes #1, Systém kotvení: -; Object Layer Attributes #1, Součinitel prostupu tepla: 0.034; Object Layer Attributes #1, Součinitel difúzního odporu: 40 - 100; Object Layer Attributes #1, Způsob spojení vrstev: Lepený
PERIMETR | Půdorys 1.NP | PERIMETR 0.22 m |  | PERIMETR |  | 1464HWa1096196322 | m3 | Celá stěna | Nový | Zateplovací systémy | PERIMETR | no | 1464Stě1096196323 | m3 | Stěna |  | 0.22 | 3.4 | 3.4 | 0.748 | 4.25 | 0.748 | 0.935 | 0.8 | NEMSOK - Object Layer Attributes #1, Kód prvku: TI02.03.0013; Object Layer Attributes #1, Požární odolnost: E; Object Layer Attributes #1, Systém kotvení: -; Object Layer Attributes #1, Součinitel prostupu tepla: 0.034; Object Layer Attributes #1, Součinitel difúzního odporu: 40 - 100; Object Layer Attributes #1, Způsob spojení vrstev: Lepený
PERIMETR | Půdorys 1.NP | PERIMETR 0.22 m | 1 | PERIMETR |  | 1464HWa1096196351 | m3 | Celá stěna | Nový | Zateplovací systémy | PERIMETR | no | 1464Stě1096196352 | m3 | Stěna |  | 0.22 | 3.256 | 3.256 | 0.716 | 4.07 | 0.716 | 0.895 | 0.8 | NEMSOK - Object Layer Attributes #1, Kód prvku: TI02.03.0014; Object Layer Attributes #1, Požární odolnost: E; Object Layer Attributes #1, Systém kotvení: -; Object Layer Attributes #1, Součinitel prostupu tepla: 0.034; Object Layer Attributes #1, Součinitel difúzního odporu: 40 - 100; Object Layer Attributes #1, Způsob spojení vrstev: Lepený
PERIMETR | Půdorys 1.NP | PERIMETR 0.22 m | 1 | PERIMETR |  | 1464HWa1096196387 | m3 | Celá stěna | Nový | Zateplovací systémy | PERIMETR | no | 1464Stě1096196388 | m3 | Stěna |  | 0.22 | 4.48 | 4.48 | 0.986 | 5.6 | 0.986 | 1.232 | 0.8 | NEMSOK - Object Layer Attributes #1, Kód prvku: TI02.03.0015; Object Layer Attributes #1, Požární odolnost: E; Object Layer Attributes #1, Systém kotvení: -; Object Layer Attributes #1, Součinitel prostupu tepla: 0.034; Object Layer Attributes #1, Součinitel difúzního odporu: 40 - 100; Object Layer Attributes #1, Způsob spojení vrstev: Lepený
PERIMETR | Půdorys 1.NP | PERIMETR 0.22 m | 1 | PERIMETR |  | 1464HWa1096196823 | m3 | Celá stěna | Nový | Zateplovací systémy | PERIMETR | no | 1464Stě1096196824 | m3 | Stěna |  | 0.22 | 0.36 | 0.36 | 0.079 | 1.8 | 0.079 | 0.396 | 0.2 | NEMSOK - Object Layer Attributes #1, Kód prvku: TI02.03.0016; Object Layer Attributes #1, Požární odolnost: E; Object Layer Attributes #1, Systém kotvení: -; Object Layer Attributes #1, Součinitel prostupu tepla: 0.034; Object Layer Attributes #1, Součinitel difúzního odporu: 40 - 100; Object Layer Attributes #1, Způsob spojení vrstev: Lepený
EPS | Půdorys 1.NP | EPS 0.02 m |  | EPS |  | 1464HWa1096213660 | m3 | Celá stěna | Nový | Zateplovací systémy | EPS | no | 1464Stě1096213665 | m3 | Stěna |  | 0.02 | 0.444 | 0.444 | 0.009 | 0.125 | 0.009 | 0.003 | 3.55 | NEMSOK - Object Layer Attributes #1, Kód prvku: TI01.03.0040; Object Layer Attributes #1, Požární odolnost: E; Object Layer Attributes #1, Systém kotvení: -; Object Layer Attributes #1, Součinitel prostupu tepla: 0.039; Object Layer Attributes #1, Součinitel difúzního odporu: 20 - 40; Object Layer Attributes #1, Způsob spojení vrstev: Mechanicky kotvený
PERIMETR | Půdorys 1.NP | PERIMETR 0.22 m | 1 | PERIMETR |  | 1464HWa1096220015 | m3 | Celá stěna | Nový | Zateplovací systémy | PERIMETR | no | 1464Stě1096220016 | m3 | Stěna |  | 0.22 | 0.7 | 0.7 | 0.154 | 3.5 | 0.154 | 0.77 | 0.2 | NEMSOK - Object Layer Attributes #1, Kód prvku: TI02.03.0017; Object Layer Attributes #1, Požární odolnost: E; Object Layer Attributes #1, Systém kotvení: -; Object Layer Attributes #1, Součinitel prostupu tepla: 0.034; Object Layer Attributes #1, Součinitel difúzního odporu: 40 - 100; Object Layer Attributes #1, Způsob spojení vrstev: Lepený
EPS | Půdorys 1.NP | EPS 0.02 m |  | EPS | E | 1464HWa1096286973 | m3 | Celá stěna | Nový | Zateplovací systémy | EPS | no | 1464Stě1096286975 | m3 | Stěna |  | 0.02 | 0.71 | 0.71 | 0.014 | 0.2 | 0.014 | 0.004 | 3.55 | NEMSOK - Object Layer Attributes #1, Kód prvku: TI01.03.0041; Object Layer Attributes #1, Požární odolnost: E; Kód prvku: TI01.03.0001; Způsob spojení vrstev: Mechanicky kotvený; Součinitel prostupu tepla: 0.039; Součinitel difúzního odporu: 20 - 40; Systém kotvení: -; Object Layer Attributes #1, Systém kotvení: -; Object Layer Attributes #1, Součinitel prostupu tepla: 0.039; Object Layer Attributes #1, Součinitel difúzního odporu: 20 - 40; Object Layer Attributes #1, Způsob spojení vrstev: Mechanicky kotvený
MINERÁLNÍ VATA | Půdorys 1.NP | MINERÁLNÍ VATA 0.3 m |  | MINERÁLNÍ VATA | A1 | 1464HWa1096159360 | m3 | Celá stěna | Nový | Zateplovací systémy | MINERÁLNÍ VATA | no | 1464Stě1096159472 | m3 | Stěna |  | 0.3 | 0.775 | 0.775 | 0.233 | 0.25 | 0.233 | 0.075 | 3.1 | NEMSOK - Object Layer Attributes #1, Kód prvku: TI06.03.0010; Object Layer Attributes #1, Požární odolnost: A1; Kód prvku: TI06.03.0001; Způsob spojení vrstev: Lepený + mechanicky kotvený; Součinitel prostupu tepla: 0.036; Součinitel difúzního odporu: 1; Systém kotvení: -; Object Layer Attributes #1, Systém kotvení: -; Object Layer Attributes #1, Součinitel prostupu tepla: 0.036; Object Layer Attributes #1, Součinitel difúzního odporu: 1; Object Layer Attributes #1, Způsob spojení vrstev: Lepený + mechanicky kotvený
EPS | Půdorys 1.NP | EPS 0.02 m |  | EPS |  | 1464HWa1096106953 | m3 | Celá stěna | Nový | Zateplovací systémy | EPS | no | 1464Stě1096106954 | m3 | Stěna |  | 0.02 | 0.71 | 0.71 | 0.014 | 0.2 | 0.014 | 0.004 | 3.55 | NEMSOK - Object Layer Attributes #1, Kód prvku: TI01.03.0002; Object Layer Attributes #1, Požární odolnost: E; Object Layer Attributes #1, Systém kotvení: -; Object Layer Attributes #1, Součinitel prostupu tepla: 0.039; Object Layer Attributes #1, Součinitel difúzního odporu: 20 - 40; Object Layer Attributes #1, Způsob spojení vrstev: Mechanicky kotvený
EPS | Půdorys 1.NP | EPS 0.02 m |  | EPS |  | 1464HWa1096106990 | m3 | Celá stěna | Nový | Zateplovací systémy | EPS | no | 1464Stě1096106992 | m3 | Stěna |  | 0.02 | 0.71 | 0.71 | 0.014 | 0.2 | 0.014 | 0.004 | 3.55 | NEMSOK - Object Layer Attributes #1, Kód prvku: TI01.03.0003; Object Layer Attributes #1, Požární odolnost: E; Object Layer Attributes #1, Systém kotvení: -; Object Layer Attributes #1, Součinitel prostupu tepla: 0.039; Object Layer Attributes #1, Součinitel difúzního odporu: 20 - 40; Object Layer Attributes #1, Způsob spojení vrstev: Mechanicky kotvený
EPS | Půdorys 1.NP | EPS 0.02 m |  | EPS |  | 1464HWa1096107393 | m3 | Celá stěna | Nový | Zateplovací systémy | EPS | no | 1464Stě1096107395 | m3 | Stěna |  | 0.02 | 0.71 | 0.71 | 0.014 | 0.2 | 0.014 | 0.004 | 3.55 | NEMSOK - Object Layer Attributes #1, Kód prvku: TI01.03.0004; Object Layer Attributes #1, Požární odolnost: E; Object Layer Attributes #1, Systém kotvení: -; Object Layer Attributes #1, Součinitel prostupu tepla: 0.039; Object Layer Attributes #1, Součinitel difúzního odporu: 20 - 40; Object Layer Attributes #1, Způsob spojení vrstev: Mechanicky kotvený
EPS | Půdorys 1.NP | EPS 0.02 m |  | EPS |  | 1464HWa1096108117 | m3 | Celá stěna | Nový | Zateplovací systémy | EPS | no | 1464Stě1096108119 | m3 | Stěna |  | 0.02 | 0.71 | 0.71 | 0.014 | 0.2 | 0.014 | 0.004 | 3.55 | NEMSOK - Object Layer Attributes #1, Kód prvku: TI01.03.0005; Object Layer Attributes #1, Požární odolnost: E; Object Layer Attributes #1, Systém kotvení: -; Object Layer Attributes #1, Součinitel prostupu tepla: 0.039; Object Layer Attributes #1, Součinitel difúzního odporu: 20 - 40; Object Layer Attributes #1, Způsob spojení vrstev: Mechanicky kotvený
EPS | Půdorys 1.NP | EPS 0.1 m |  | EPS |  | 1464HWa1096135645 | m3 | Celá stěna | Nový | Zateplovací systémy | EPS | no | 1464Stě1096135646 | m3 | Stěna |  | 0.1 | 1.86 | 1.86 | 0.186 | 0.6 | 0.186 | 0.06 | 3.1 | NEMSOK - Object Layer Attributes #1, Kód prvku: TI01.03.0006; Object Layer Attributes #1, Požární odolnost: E; Object Layer Attributes #1, Systém kotvení: -; Object Layer Attributes #1, Součinitel prostupu tepla: 0.039; Object Layer Attributes #1, Součinitel difúzního odporu: 20 - 40; Object Layer Attributes #1, Způsob spojení vrstev: Lepený + mechanicky kotvený
EPS | Půdorys 1.NP | EPS 0.02 m |  | EPS |  | 1464HWa1096140379 | m3 | Celá stěna | Nový | Zateplovací systémy | EPS | no | 1464Stě1096140380 | m3 | Stěna |  | 0.02 | 0.71 | 0.71 | 0.014 | 0.2 | 0.014 | 0.004 | 3.55 | NEMSOK - Object Layer Attributes #1, Kód prvku: TI01.03.0007; Object Layer Attributes #1, Požární odolnost: E; Object Layer Attributes #1, Systém kotvení: -; Object Layer Attributes #1, Součinitel prostupu tepla: 0.039; Object Layer Attributes #1, Součinitel difúzního odporu: 20 - 40; Object Layer Attributes #1, Způsob spojení vrstev: Mechanicky kotvený
EPS | Půdorys 1.NP | EPS 0.02 m |  | EPS |  | 1464HWa1096140545 | m3 | Celá stěna | Nový | Zateplovací systémy | EPS | no | 1464Stě1096140546 | m3 | Stěna |  | 0.02 | 0.71 | 0.71 | 0.014 | 0.2 | 0.014 | 0.004 | 3.55 | NEMSOK - Object Layer Attributes #1, Kód prvku: TI01.03.0009; Object Layer Attributes #1, Požární odolnost: E; Object Layer Attributes #1, Systém kotvení: -; Object Layer Attributes #1, Součinitel prostupu tepla: 0.039; Object Layer Attributes #1, Součinitel difúzního odporu: 20 - 40; Object Layer Attributes #1, Způsob spojení vrstev: Mechanicky kotvený
EPS | Půdorys 1.NP | EPS 0.02 m |  | EPS |  | 1464HWa1096140662 | m3 | Celá stěna | Nový | Zateplovací systémy | EPS | no | 1464Stě1096140664 | m3 | Stěna |  | 0.02 | 0.71 | 0.71 | 0.014 | 0.2 | 0.014 | 0.004 | 3.55 | NEMSOK - Object Layer Attributes #1, Kód prvku: TI01.03.0010; Object Layer Attributes #1, Požární odolnost: E; Object Layer Attributes #1, Systém kotvení: -; Object Layer Attributes #1, Součinitel prostupu tepla: 0.039; Object Layer Attributes #1, Součinitel difúzního odporu: 20 - 40; Object Layer Attributes #1, Způsob spojení vrstev: Mechanicky kotvený
EPS | Půdorys 1.NP | EPS 0.02 m |  | EPS |  | 1464HWa1096145034 | m3 | Celá stěna | Nový | Zateplovací systémy | EPS | no | 1464Stě1096145036 | m3 | Stěna |  | 0.02 | 0.71 | 0.71 | 0.014 | 0.2 | 0.014 | 0.004 | 3.55 | NEMSOK - Object Layer Attributes #1, Kód prvku: TI01.03.0011; Object Layer Attributes #1, Požární odolnost: E; Object Layer Attributes #1, Systém kotvení: -; Object Layer Attributes #1, Součinitel prostupu tepla: 0.039; Object Layer Attributes #1, Součinitel difúzního odporu: 20 - 40; Object Layer Attributes #1, Způsob spojení vrstev: Mechanicky kotvený
ZELEZOBETONOVÁ KCE | Půdorys 1.NP | ZELEZOBETONOVÁ KCE 0.25 m, MINERÁLNÍ VATA 0.3 m |  | ZELEZOBETONOVÁ KCE |  | 1464HWa1096156934 | m3 | Celá stěna | Nový | Betonářské práce | ZELEZOBETONOVÁ KCE | yes | 1464Stě1096157350 | m3 | Stěna |  | 0.55 | 29.642 | 27.393 | 15.223 | 8.375 | 13.985 | 4.607 | 3.55 | NEMSOK - Object Layer Attributes #2, 2D interakce: yes; Object Layer Attributes #2, Status: Nový; Object Layer Attributes #2, Práce: Zateplovací systémy; Object Layer Attributes #2, Materiál: MINERÁLNÍ VATA; Object Layer Attributes #2, Allright_Stavebni_dil_ID: 1464Stě1096157354; Object Layer Attributes #2, Jednotka: m3; Object Layer Attributes #2, Název_objektu: Stěna; Object Layer Attributes #2, Staticky nosná konstrukce: no; Object Layer Attributes #1, Kód prvku: SN02.03.0011; Object Layer Attributes #1, Funkce: Ano; Object Layer Attributes #1, U-hodnota: 3.05; Object Layer Attributes #1, Podlaží: 1.NP; Object Layer Attributes #1, Požární odolnost: A; Object Layer Attributes #1, Třída pevnosti ocele: B500B; Object Layer Attributes #1, Stupeň vyztužení: 150; Object Layer Attributes #1, Třída pevnosti betonu: C25/30-XC1; Object Layer Attributes #1, Krytí výztuže: 25mm; Object Layer Attributes #1, Statická funkce: Ano; Object Layer Attributes #2, Kód prvku: TI06.03.0006; Object Layer Attributes #2, Požární odolnost: A1; Object Layer Attributes #2, Součinitel prostupu tepla: 0.036; Object Layer Attributes #2, Součinitel difúzního odporu: 1; Object Layer Attributes #2, Způsob spojení vrstev: Lepený + mechanicky kotvený; Object Layer Attributes #2, Systém kotvení: -
YTONG 300 | Půdorys 1.NP | YTONG 300 0.3 m |  | YTONG 300 | REI 180 | 1464HWa0000003331 | m3 | Celá stěna | Nový | Zednické práce | YTONG 300 | no | 1464Stě0000003332 | m3 | Stěna | 0.541 | 0.3 | 2.48 | 2.48 | 0.744 | 0.8 | 0.744 | 0.24 | 3.1 | Pset_WallCommon - AcousticRating: 48 dB; NEMSOK - Object Layer Attributes #1, Kód prvku: SN06.03.1001; Object Layer Attributes #1, Funkce: Ne; Object Layer Attributes #1, U-hodnota: 0.362; Object Layer Attributes #1, Podlaží: 1.NP; Object Layer Attributes #1, Neprůzvučnost: 44 dB; Object Layer Attributes #1, Požární odolnost: REI 180; Object Layer Attributes #1, Pevnost zdiva: 2,32 N/mm2; Object Layer Attributes #1, Funkce (venkovní): Ne; Object Layer Attributes #1, Statická funkce: Ne
YTONG 300 | Půdorys 1.NP | YTONG 300 0.3 m |  | YTONG 300 | REI 180 | 1464HWa0000003336 | m3 | Celá stěna | Nový | Zednické práce | YTONG 300 | no | 1464Stě0000003337 | m3 | Stěna | 0.541 | 0.3 | 2.25 | 2.25 | 0.675 | 1 | 0.675 | 0.3 | 2.25 | Pset_WallCommon - AcousticRating: 48 dB; NEMSOK - Object Layer Attributes #1, Kód prvku: SN06.03.1002; Object Layer Attributes #1, Funkce: Ne; Object Layer Attributes #1, U-hodnota: 0.362; Object Layer Attributes #1, Podlaží: 1.NP; Object Layer Attributes #1, Neprůzvučnost: 44 dB; Object Layer Attributes #1, Požární odolnost: REI 180; Object Layer Attributes #1, Pevnost zdiva: 2,32 N/mm2; Object Layer Attributes #1, Funkce (venkovní): Ne; Object Layer Attributes #1, Statická funkce: Ne
YTONG 300 | Půdorys 1.NP | YTONG 300 0.3 m |  | YTONG 300 | REI 180 | 1464HWa1096157175 | m3 | Celá stěna | Nový | Zednické práce | YTONG 300 | no | 1464Stě1096157629 | m3 | Stěna | 0.541 | 0.3 | 3.06 | 3.06 | 0.918 | 1.5 | 0.918 | 0.45 | 2.04 | Pset_WallCommon - AcousticRating: 48 dB; NEMSOK - Object Layer Attributes #1, Kód prvku: SN06.03.1003; Object Layer Attributes #1, Funkce: Ne; Object Layer Attributes #1, U-hodnota: 0.362; Object Layer Attributes #1, Podlaží: 1.NP; Object Layer Attributes #1, Neprůzvučnost: 44 dB; Object Layer Attributes #1, Požární odolnost: REI 180; Object Layer Attributes #1, Pevnost zdiva: 2,32 N/mm2; Object Layer Attributes #1, Funkce (venkovní): Ne; Object Layer Attributes #1, Statická funkce: Ne
YTONG 300 | Půdorys 1.NP | YTONG 300 0.3 m |  | YTONG 300 | REI 180 | 1464HWa1096157177 | m3 | Celá stěna | Nový | Zednické práce | YTONG 300 | no | 1464Stě1096157633 | m3 | Stěna | 0.541 | 0.3 | 3.06 | 3.041 | 0.918 | 1.5 | 0.912 | 0.45 | 2.04 | Pset_WallCommon - AcousticRating: 48 dB; NEMSOK - Object Layer Attributes #1, Kód prvku: SN06.03.1004; Object Layer Attributes #1, Funkce: Ne; Object Layer Attributes #1, U-hodnota: 0.362; Object Layer Attributes #1, Podlaží: 1.NP; Object Layer Attributes #1, Neprůzvučnost: 44 dB; Object Layer Attributes #1, Požární odolnost: REI 180; Object Layer Attributes #1, Pevnost zdiva: 2,32 N/mm2; Object Layer Attributes #1, Funkce (venkovní): Ne; Object Layer Attributes #1, Statická funkce: Ne
YTONG 300 | Půdorys 1.NP | YTONG 300 0.3 m |  | YTONG 300 | REI 180 | 1464HWa1096157999 | m3 | Celá stěna | Nový | Zednické práce | YTONG 300 | no | 1464Stě1096159495 | m3 | Stěna | 0.541 | 0.3 | 3.45 | 0.15 | 1.035 | 1.5 | 0.045 | 0.45 | 2.3 | Pset_WallCommon - AcousticRating: 48 dB; NEMSOK - Object Layer Attributes #1, Kód prvku: SN06.03.1005; Object Layer Attributes #1, Funkce: Ne; Object Layer Attributes #1, U-hodnota: 0.362; Object Layer Attributes #1, Podlaží: 1.NP; Object Layer Attributes #1, Neprůzvučnost: 44 dB; Object Layer Attributes #1, Požární odolnost: REI 180; Object Layer Attributes #1, Pevnost zdiva: 2,32 N/mm2; Object Layer Attributes #1, Funkce (venkovní): Ne; Object Layer Attributes #1, Statická funkce: Ne
YTONG 250 | Půdorys 1.NP | YTONG 250 |  | YTONG 250 | REI 180 | 1464HWa1096213602 | m3 | Celá stěna | Nový | Zednické práce | YTONG 250 | no | 1464Stě1096213603 | m3 | Stěna | 0.637 | 0.25 | 42.874 | 29.023 | 10.719 | 13.525 | 7.256 | 3.381 | 3.17 | Pset_WallCommon - AcousticRating: 47 dB; NEMSOK - Object Layer Attributes #1, Kód prvku: SN06.03.0001; Object Layer Attributes #1, Funkce: Ne; Object Layer Attributes #1, U-hodnota: 0.429; Object Layer Attributes #1, Podlaží: 1.NP; Object Layer Attributes #1, Neprůzvučnost: 43 dB; Object Layer Attributes #1, Požární odolnost: REI 180; Object Layer Attributes #1, Pevnost zdiva: 2,32 N/mm2; Object Layer Attributes #1, Funkce (venkovní): Ne; Object Layer Attributes #1, Statická funkce: Ne
YTONG 300 | Půdorys 1.NP | YTONG 300 |  | YTONG 300 | REI 180 | 1464HWa1096215233 | m3 | Celá stěna | Nový | Zednické práce | YTONG 300 | no | 1464Stě1096215266 | m3 | Stěna | 0.541 | 0.3 | 6.578 | 3.392 | 1.973 | 2.075 | 1.018 | 0.623 | 3.17 | Pset_WallCommon - AcousticRating: 48 dB; NEMSOK - Object Layer Attributes #1, Kód prvku: SN06.03.1008; Object Layer Attributes #1, Funkce: Ne; Object Layer Attributes #1, U-hodnota: 0.362; Object Layer Attributes #1, Podlaží: 1.NP; Object Layer Attributes #1, Neprůzvučnost: 44 dB; Object Layer Attributes #1, Požární odolnost: REI 180; Object Layer Attributes #1, Pevnost zdiva: 2,32 N/mm2; Object Layer Attributes #1, Funkce (venkovní): Ne; Object Layer Attributes #1, Statická funkce: Ne
YTONG 300 | Půdorys 1.NP | YTONG 300 0.3 m |  | YTONG 300 | REI 180 | 1464HWa1096158001 | m3 | Celá stěna | Nový | Zednické práce | YTONG 300 | no | 1464Stě1096159497 | m3 | Stěna | 0.541 | 0.3 | 0.969 | 0.876 | 0.291 | 1.02 | 0.263 | 0.306 | 0.95 | Pset_WallCommon - AcousticRating: 48 dB; NEMSOK - Object Layer Attributes #1, Kód prvku: SN06.03.1006; Object Layer Attributes #1, Funkce: Ne; Object Layer Attributes #1, U-hodnota: 0.362; Object Layer Attributes #1, Podlaží: 1.NP; Object Layer Attributes #1, Neprůzvučnost: 44 dB; Object Layer Attributes #1, Požární odolnost: REI 180; Object Layer Attributes #1, Pevnost zdiva: 2,32 N/mm2; Object Layer Attributes #1, Funkce (venkovní): Ne; Object Layer Attributes #1, Statická funkce: Ne
YTONG 300 | Půdorys 1.NP | YTONG 300 0.3 m |  | YTONG 300 | REI 180 | 1464HWa1096157997 | m3 | Celá stěna | Nový | Zednické práce | YTONG 300 | no | 1464Stě1096159499 | m3 | Stěna | 0.541 | 0.3 | 1.008 | 1.008 | 0.302 | 0.48 | 0.302 | 0.144 | 2.1 | Pset_WallCommon - AcousticRating: 48 dB; NEMSOK - Object Layer Attributes #1, Kód prvku: SN06.03.1007; Object Layer Attributes #1, Funkce: Ne; Object Layer Attributes #1, U-hodnota: 0.362; Object Layer Attributes #1, Podlaží: 1.NP; Object Layer Attributes #1, Neprůzvučnost: 44 dB; Object Layer Attributes #1, Požární odolnost: REI 180; Object Layer Attributes #1, Pevnost zdiva: 2,32 N/mm2; Object Layer Attributes #1, Funkce (venkovní): Ne; Object Layer Attributes #1, Statická funkce: Ne
YTONG 100 | Půdorys 1.NP | YTONG 100 0.1 m |  | YTONG 100 | EI 120 | 1464HWa0000003856 | m3 | Celá stěna | Nový | Zednické práce | YTONG 100 | no | 1464Stě0000003857 | m3 | Stěna | 1.111 | 0.1 | 1.908 | 1.908 | 0.191 | 0.9 | 0.191 | 0.09 | 2.12 | Pset_WallCommon - AcousticRating: 37 dB; NEMSOK - Object Layer Attributes #1, Kód prvku: SN06.03.1001; Object Layer Attributes #1, Funkce: Ne; Object Layer Attributes #1, U-hodnota: 1.111; Object Layer Attributes #1, Podlaží: 1.NP; Object Layer Attributes #1, Neprůzvučnost: 35 dB; Object Layer Attributes #1, Požární odolnost: EI 120; Object Layer Attributes #1, Pevnost zdiva: 1,92 N/mm2; Object Layer Attributes #1, Funkce (venkovní): Ne; Object Layer Attributes #1, Statická funkce: Ne
YTONG 100 | Půdorys 1.NP | YTONG 100 0.1 m |  | YTONG 100 | EI 120 | 1464HWa1096135771 | m3 | Celá stěna | Nový | Zednické práce | YTONG 100 | no | 1464Stě1096135772 | m3 | Stěna | 1.111 | 0.1 | 2.48 | 2.48 | 0.248 | 0.8 | 0.248 | 0.08 | 3.1 | Pset_WallCommon - AcousticRating: 37 dB; NEMSOK - Object Layer Attributes #1, Kód prvku: SN06.03.1002; Object Layer Attributes #1, Funkce: Ne; Object Layer Attributes #1, U-hodnota: 1.111; Object Layer Attributes #1, Podlaží: 1.NP; Object Layer Attributes #1, Neprůzvučnost: 35 dB; Object Layer Attributes #1, Požární odolnost: EI 120; Object Layer Attributes #1, Pevnost zdiva: 1,92 N/mm2; Object Layer Attributes #1, Funkce (venkovní): Ne; Object Layer Attributes #1, Statická funkce: Ne
YTONG 125 | Půdorys 1.NP | YTONG 125 0.125 m |  | YTONG 125 | EI 180 | 1464HWa1096159364 | m3 | Celá stěna | Nový | Zednické práce | YTONG 125 | no | 1464Stě1096159555 | m3 | Stěna | 0.926 | 0.125 | 0.745 | 0.746 | 0.093 | 0.21 | 0.093 | 0.026 | 3.55 | Pset_WallCommon - AcousticRating: 39 dB; NEMSOK - Object Layer Attributes #1, Kód prvku: SN06.03.2001; Object Layer Attributes #1, Funkce: Ne; Object Layer Attributes #1, U-hodnota: 0.926; Object Layer Attributes #1, Podlaží: 1.NP; Object Layer Attributes #1, Neprůzvučnost: 37 dB; Object Layer Attributes #1, Požární odolnost: EI 180; Object Layer Attributes #1, Pevnost zdiva: 1,92 N/mm2; Object Layer Attributes #1, Funkce (venkovní): Ne; Object Layer Attributes #1, Statická funkce: Ne
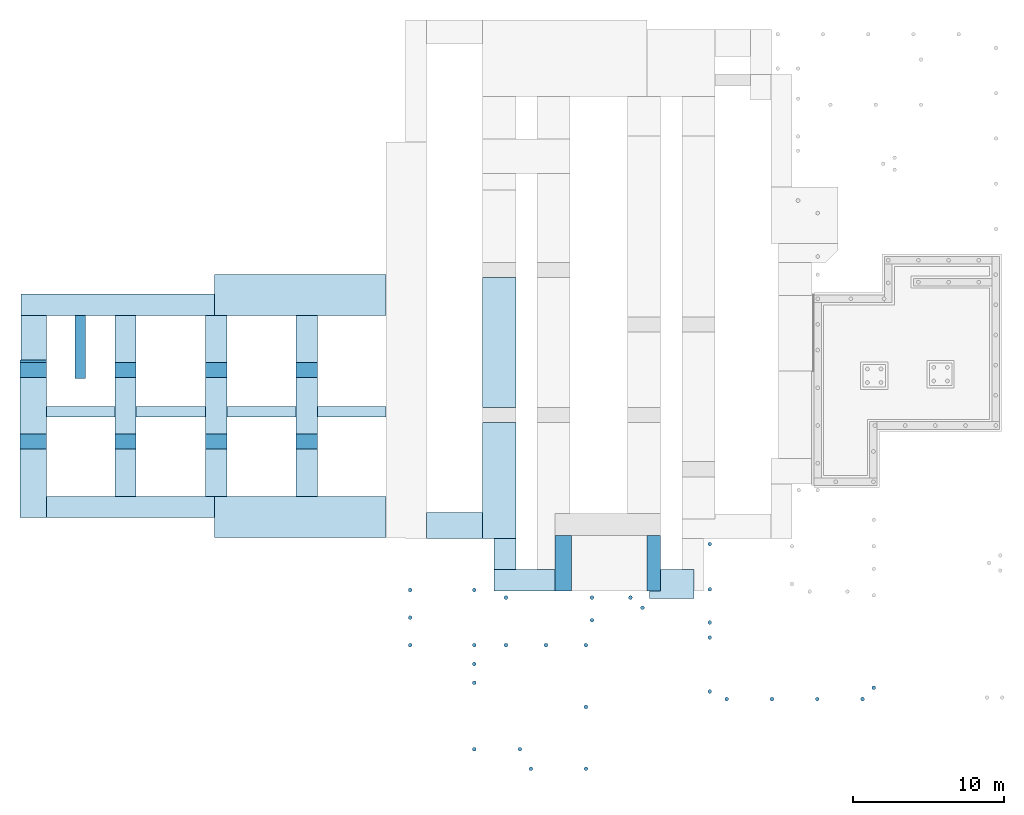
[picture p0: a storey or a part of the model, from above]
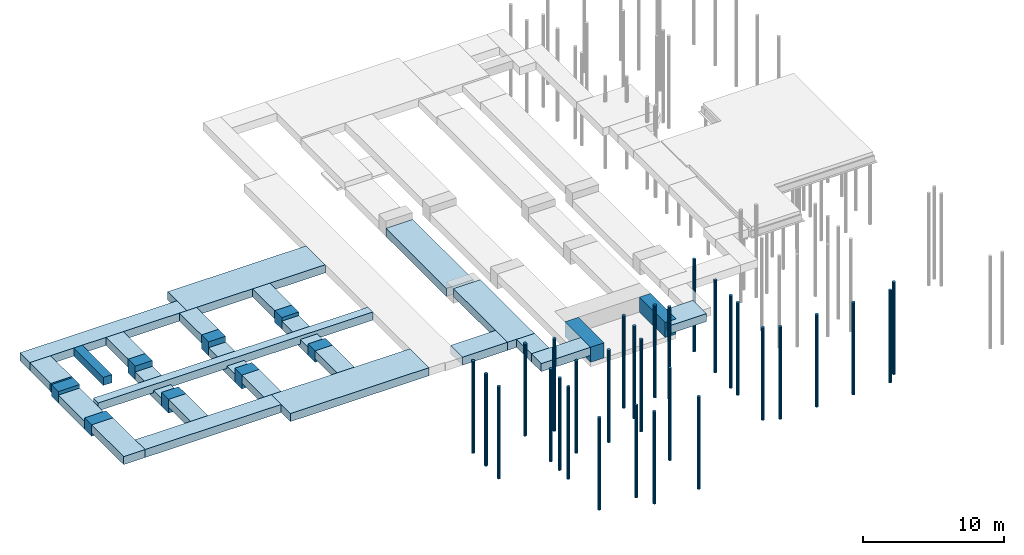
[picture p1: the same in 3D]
Properties of the parts of a building model (IFC4), part 34 of 45

# IfcWall (2385)
Name | In | Material | Faktor | Označení | Požární odolnost | Allright_Stavebni_dil_ID | Jednotka | Název_objektu | Object Layer Attributes #1, Status | Object Layer Attributes #1, Práce | Object Layer Attributes #1, Materiál | Object Layer Attributes #1, Staticky nosná konstrukce | Object Layer Attributes #1, Allright_Stavebni_dil_ID | Object Layer Attributes #1, Jednotka | Object Layer Attributes #1, Název_objektu | ThermalTransmittance (W/K/m2) | Width (m) | GrossSideArea (m2) | NetSideArea (m2) | GrossVolume (m3) | Length (m) | NetVolume (m3) | GrossFootprintArea (m2) | Height (m)
YTONG 125 | Půdorys 1.NP | YTONG 125 0.125 m |  | YTONG 125 | EI 180 | 1464HWa1096159366 | m3 | Celá stěna | Nový | Zednické práce | YTONG 125 | no | 1464Stě1096159561 | m3 | Stěna | 0.926 | 0.125 | 0.745 | 0.746 | 0.093 | 0.21 | 0.093 | 0.026 | 3.55 | Pset_WallCommon - AcousticRating: 39 dB; NEMSOK - Object Layer Attributes #1, Kód prvku: SN06.03.2002; Object Layer Attributes #1, Funkce: Ne; Object Layer Attributes #1, U-hodnota: 0.926; Object Layer Attributes #1, Podlaží: 1.NP; Object Layer Attributes #1, Neprůzvučnost: 37 dB; Object Layer Attributes #1, Požární odolnost: EI 180; Object Layer Attributes #1, Pevnost zdiva: 1,92 N/mm2; Object Layer Attributes #1, Funkce (venkovní): Ne; Object Layer Attributes #1, Statická funkce: Ne
YTONG 125 | Půdorys 1.NP | YTONG 125 0.125 m |  | YTONG 125 | EI 180 | 1464HWa1096159372 | m3 | Celá stěna | Nový | Zednické práce | YTONG 125 | no | 1464Stě1096159573 | m3 | Stěna | 0.926 | 0.125 | 0.592 | 0.592 | 0.074 | 0.16 | 0.074 | 0.02 | 3.7 | Pset_WallCommon - AcousticRating: 39 dB; NEMSOK - Object Layer Attributes #1, Kód prvku: SN06.03.2003; Object Layer Attributes #1, Funkce: Ne; Object Layer Attributes #1, U-hodnota: 0.926; Object Layer Attributes #1, Podlaží: 1.NP; Object Layer Attributes #1, Neprůzvučnost: 37 dB; Object Layer Attributes #1, Požární odolnost: EI 180; Object Layer Attributes #1, Pevnost zdiva: 1,92 N/mm2; Object Layer Attributes #1, Funkce (venkovní): Ne; Object Layer Attributes #1, Statická funkce: Ne
YTONG 125 | Půdorys 1.NP | YTONG 125 0.125 m |  | YTONG 125 | EI 180 | 1464HWa1096161089 | m3 | Celá stěna | Nový | Zednické práce | YTONG 125 | no | 1464Stě1096161090 | m3 | Stěna | 0.926 | 0.125 | 2.07 | 0.374 | 0.259 | 0.9 | 0.047 | 0.113 | 2.3 | Pset_WallCommon - AcousticRating: 39 dB; NEMSOK - Object Layer Attributes #1, Kód prvku: SN06.03.2004; Object Layer Attributes #1, Funkce: Ne; Object Layer Attributes #1, U-hodnota: 0.926; Object Layer Attributes #1, Podlaží: 1.NP; Object Layer Attributes #1, Neprůzvučnost: 37 dB; Object Layer Attributes #1, Požární odolnost: EI 180; Object Layer Attributes #1, Pevnost zdiva: 1,92 N/mm2; Object Layer Attributes #1, Funkce (venkovní): Ne; Object Layer Attributes #1, Statická funkce: Ne
YTONG 125 | Půdorys 1.NP | YTONG 125 0.125 m |  | YTONG 125 | EI 180 | 1464HWa1096163814 | m3 | Celá stěna | Nový | Zednické práce | YTONG 125 | no | 1464Stě1096163816 | m3 | Stěna | 0.926 | 0.125 | 0.851 | 0.851 | 0.106 | 0.23 | 0.106 | 0.029 | 3.7 | Pset_WallCommon - AcousticRating: 39 dB; NEMSOK - Object Layer Attributes #1, Kód prvku: SN06.03.2006; Object Layer Attributes #1, Funkce: Ne; Object Layer Attributes #1, U-hodnota: 0.926; Object Layer Attributes #1, Podlaží: 1.NP; Object Layer Attributes #1, Neprůzvučnost: 37 dB; Object Layer Attributes #1, Požární odolnost: EI 180; Object Layer Attributes #1, Pevnost zdiva: 1,92 N/mm2; Object Layer Attributes #1, Funkce (venkovní): Ne; Object Layer Attributes #1, Statická funkce: Ne
YTONG 125 | Půdorys 1.NP | YTONG 125 0.125 m |  | YTONG 125 | EI 180 | 1464HWa1096163817 | m3 | Celá stěna | Nový | Zednické práce | YTONG 125 | no | 1464Stě1096163819 | m3 | Stěna | 0.926 | 0.125 | 0.777 | 0.777 | 0.097 | 0.21 | 0.097 | 0.026 | 3.7 | Pset_WallCommon - AcousticRating: 39 dB; NEMSOK - Object Layer Attributes #1, Kód prvku: SN06.03.2007; Object Layer Attributes #1, Funkce: Ne; Object Layer Attributes #1, U-hodnota: 0.926; Object Layer Attributes #1, Podlaží: 1.NP; Object Layer Attributes #1, Neprůzvučnost: 37 dB; Object Layer Attributes #1, Požární odolnost: EI 180; Object Layer Attributes #1, Pevnost zdiva: 1,92 N/mm2; Object Layer Attributes #1, Funkce (venkovní): Ne; Object Layer Attributes #1, Statická funkce: Ne
YTONG 125 | Půdorys 1.NP | YTONG 125 0.125 m |  | YTONG 125 | EI 180 | 1464HWa1096206173 | m3 | Celá stěna | Nový | Zednické práce | YTONG 125 | no | 1464Stě1096206174 | m3 | Stěna | 0.926 | 0.125 | 2.544 | 0.424 | 0.318 | 1.2 | 0.053 | 0.15 | 2.12 | Pset_WallCommon - AcousticRating: 39 dB; NEMSOK - Object Layer Attributes #1, Kód prvku: SN06.03.2008; Object Layer Attributes #1, Funkce: Ne; Object Layer Attributes #1, U-hodnota: 0.926; Object Layer Attributes #1, Podlaží: 1.NP; Object Layer Attributes #1, Neprůzvučnost: 37 dB; Object Layer Attributes #1, Požární odolnost: EI 180; Object Layer Attributes #1, Pevnost zdiva: 1,92 N/mm2; Object Layer Attributes #1, Funkce (venkovní): Ne; Object Layer Attributes #1, Statická funkce: Ne
YTONG 125 | Půdorys 1.NP | YTONG 125 0.125 m |  | YTONG 125 | EI 180 | 1464HWa1096213662 | m3 | Celá stěna | Nový | Zednické práce | YTONG 125 | no | 1464Stě1096213664 | m3 | Stěna | 0.926 | 0.125 | 0.777 | 0.777 | 0.097 | 0.21 | 0.097 | 0.026 | 3.7 | Pset_WallCommon - AcousticRating: 39 dB; NEMSOK - Object Layer Attributes #1, Kód prvku: SN06.03.2009; Object Layer Attributes #1, Funkce: Ne; Object Layer Attributes #1, U-hodnota: 0.926; Object Layer Attributes #1, Podlaží: 1.NP; Object Layer Attributes #1, Neprůzvučnost: 37 dB; Object Layer Attributes #1, Požární odolnost: EI 180; Object Layer Attributes #1, Pevnost zdiva: 1,92 N/mm2; Object Layer Attributes #1, Funkce (venkovní): Ne; Object Layer Attributes #1, Statická funkce: Ne
YTONG 150 | Půdorys 1.NP | YTONG 150 0.15 m |  | YTONG 150 | EI 180 | 1464HWa1096277152 | m3 | Celá stěna | Nový | Zednické práce | YTONG 150 | no | 1464Stě1096277153 | m3 | Stěna | 0.794 | 0.15 | 0.66 | 0.66 | 0.099 | 0.3 | 0.099 | 0.045 | 2.2 | Pset_WallCommon - AcousticRating: 41 dB; NEMSOK - Object Layer Attributes #1, Kód prvku: SN06.03.3001; Object Layer Attributes #1, Funkce: Ne; Object Layer Attributes #1, U-hodnota: 0.794; Object Layer Attributes #1, Podlaží: 1.NP; Object Layer Attributes #1, Neprůzvučnost: 39 dB; Object Layer Attributes #1, Požární odolnost: EI 180; Object Layer Attributes #1, Pevnost zdiva: 1,92 N/mm2; Object Layer Attributes #1, Funkce (venkovní): Ne
YTONG 125 | Půdorys 1.NP | YTONG 125 0.125 m |  | YTONG 125 | EI 180 | 1464HWa1096164054 | m3 | Celá stěna | Stávající | Zednické práce | YTONG 125 | no | 1464Stě1096164075 | m3 | Stěna | 0.926 | 0.125 | 2.875 | 0 | 0.359 | 1.25 | 0 | 0.156 | 2.3 | Pset_WallCommon - AcousticRating: 39 dB; NEMSOK - Object Layer Attributes #1, Podlaží: 1.NP
YTONG 100 | Půdorys 1.NP | YTONG 100 0.1 m |  | YTONG 100 |  | 1464HWa1096316173 | m3 | Celá stěna | Nový | Zednické práce | YTONG 100 | no | 1464Stě1096316174 | m3 | Stěna |  | 0.1 | 6.449 | 0 | 0.645 | 1.925 | 0 | 0.193 | 3.35 | NEMSOK - Object Layer Attributes #1, Kód prvku: SN06.03.1003; Object Layer Attributes #1, Funkce: Ne; Object Layer Attributes #1, U-hodnota: 1.111; Object Layer Attributes #1, Podlaží: 1.NP; Object Layer Attributes #1, Neprůzvučnost: 35 dB; Object Layer Attributes #1, Požární odolnost: EI 120; Object Layer Attributes #1, Pevnost zdiva: 1,92 N/mm2; Object Layer Attributes #1, Funkce (venkovní): Ne; Object Layer Attributes #1, Statická funkce: Ne
YTONG 125 | Půdorys 1.NP | YTONG 125 0.125 m |  | YTONG 125 | EI 180 | 1464HWa1096157575 | m3 | Celá stěna | Stávající | Zednické práce | YTONG 125 | no | 1464Stě1096157582 | m3 | Stěna | 0.926 | 0.125 | 3.286 | 0 | 0.411 | 1.55 | 0 | 0.194 | 2.12 | Pset_WallCommon - AcousticRating: 39 dB; NEMSOK - Object Layer Attributes #1, Podlaží: 1.NP
YTONG 125 | Půdorys 1.NP | YTONG 125 0.125 m |  | YTONG 125 | EI 180 | 1464HWa1096163791 | m3 | Celá stěna | Stávající | Zednické práce | YTONG 125 | no | 1464Stě1096163809 | m3 | Stěna | 0.926 | 0.125 | 1.908 | 0 | 0.238 | 0.9 | 0 | 0.112 | 2.12 | Pset_WallCommon - AcousticRating: 39 dB; NEMSOK - Object Layer Attributes #1, Funkce: Ne; Object Layer Attributes #1, U-hodnota: 0.926; Object Layer Attributes #1, Podlaží: 1.NP; Object Layer Attributes #1, Neprůzvučnost: 37 dB; Object Layer Attributes #1, Požární odolnost: EI 180
YTONG 125 | Půdorys 1.NP | YTONG 125 0.125 m |  | YTONG 125 | EI 180 | 1464HWa1096288780 | m3 | Celá stěna | Stávající | Zednické práce | YTONG 125 |  | 1464Stě1096288784 | m3 | Stěna | 0.926 | 0.125 | 2.12 | 0 | 0.265 | 1 | 0 | 0.125 | 2.12 | Pset_WallCommon - AcousticRating: 39 dB; NEMSOK - Object Layer Attributes #1, Podlaží: 1.NP
DĚLÍCÍ PŘÍČKA | Půdorys 1.NP | DĚLÍCÍ PŘÍČKA 0.032 m |  | DĚLÍCÍ PŘÍČKA |  | 1464HWa1096124877 | m3 | Celá stěna | Nový | Suché stavební práce | DĚLÍCÍ PŘÍČKA | no | 1464Stě1096124878 | m3 | Stěna |  | 0.032 | 2.64 | 2.64 | 0.084 | 1.2 | 0.084 | 0.038 | 2.2 | NEMSOK - Object Layer Attributes #1, Kód prvku: TV00.03.2001; Object Layer Attributes #1, Podlaží: 1.NP; Object Layer Attributes #1, Číslo místnosti: K1.09
DĚLÍCÍ PŘÍČKA | Půdorys 1.NP | DĚLÍCÍ PŘÍČKA 0.032 m |  | DĚLÍCÍ PŘÍČKA |  | 1464HWa1096144071 | m3 | Celá stěna | Nový | Suché stavební práce | DĚLÍCÍ PŘÍČKA | no | 1464Stě1096144072 | m3 | Stěna |  | 0.032 | 1.828 | 1.097 | 0.058 | 2.15 | 0.035 | 0.069 | 0.85 | NEMSOK - Object Layer Attributes #1, Kód prvku: TV00.03.2002; Object Layer Attributes #1, Podlaží: 1.NP; Object Layer Attributes #1, Číslo místnosti: K1.08
PROSKLENÁ PŘÍČKA JEDNODUCHÁ | Půdorys 1.NP | PROSKLENÁ FASÁDA 0.055 m |  | PROSKLENÁ PŘÍČKA JEDNODUCHÁ | bez požadavku | 1464HWa1096156617 | m3 | Celá stěna | Nový | Zavěšené fasády | PROSKLENÁ FASÁDA | no | 1464Stě1096159356 | m3 | Stěna | 0.7 | 0.055 | 22.632 | 17.704 | 1.245 | 6.9 | 0.974 | 0.379 | 3.28 | Pset_WallCommon - AcousticRating: 37 dB; NEMSOK - Object Layer Attributes #1, Kód prvku: LP01.02.0001; Object Layer Attributes #1, Funkce (venkovní): Ano
ZELEZOBETONOVÁ KCE | Půdorys 1.NP | ZELEZOBETONOVÁ KCE 0.25 m, MINERÁLNÍ VATA 0.3 m |  | ZELEZOBETONOVÁ KCE |  | 1464HWa1096157873 | m3 | Celá stěna | Nový | Betonářské práce | ZELEZOBETONOVÁ KCE | yes | 1464Stě1096159800 | m3 | Stěna |  | 0.55 | 41.921 | 41.921 | 21.315 | 11.49 | 21.31 | 6.328 | 3.7 | NEMSOK - Object Layer Attributes #2, 2D interakce: yes; Object Layer Attributes #2, Status: Nový; Object Layer Attributes #2, Práce: Zateplovací systémy; Object Layer Attributes #2, Materiál: MINERÁLNÍ VATA; Object Layer Attributes #2, Allright_Stavebni_dil_ID: 1464Stě1096159698; Object Layer Attributes #2, Jednotka: m3; Object Layer Attributes #2, Název_objektu: Stěna; Object Layer Attributes #2, Staticky nosná konstrukce: no; Object Layer Attributes #1, Kód prvku: SN02.03.0036; Object Layer Attributes #1, Funkce: Ano; Object Layer Attributes #1, U-hodnota: 3.05; Object Layer Attributes #1, Podlaží: 1.NP; Object Layer Attributes #1, Požární odolnost: A; Object Layer Attributes #1, Třída pevnosti ocele: B500B; Object Layer Attributes #1, Stupeň vyztužení: 150; Object Layer Attributes #1, Třída pevnosti betonu: C25/30-XC1; Object Layer Attributes #1, Krytí výztuže: 25mm; Object Layer Attributes #1, Statická funkce: Ano; Object Layer Attributes #2, Kód prvku: TI06.03.0013; Object Layer Attributes #2, Požární odolnost: A1; Object Layer Attributes #2, Součinitel prostupu tepla: 0.036; Object Layer Attributes #2, Součinitel difúzního odporu: 1; Object Layer Attributes #2, Způsob spojení vrstev: Lepený + mechanicky kotvený; Object Layer Attributes #2, Systém kotvení: -
SDK - OCEL. KCE + 2 OPLÁŠTĚNÍ | Půdorys 1.NP | SDK - OCEL. KCE + 2 OPLÁŠTĚNÍ 0.1 m |  | SDK - OCEL. KCE + 2 OPLÁŠTĚNÍ |  | 1464HWa1096174118 | m3 | Celá stěna | Nový | Suché stavební práce | SDK - OCEL. KCE + 2 OPLÁŠTĚNÍ | no | 1464Stě1096174119 | m3 | Stěna |  | 0.1 | 4.14 | 4.1 | 0.414 | 6.9 | 0.41 | 0.69 | 0.6 | NEMSOK - Object Layer Attributes #1, Kód prvku: ZV00.03.2001; Object Layer Attributes #1, Podlaží: 1.NP; Object Layer Attributes #1, Požární odolnost: bez požadavku; Object Layer Attributes #1, Funkce (venkovní): Ne; Object Layer Attributes #1, Vlhkostní namáhání oboustranné: Ne; Object Layer Attributes #1, Tloušťka opláštění: 2×12,5; Object Layer Attributes #1, Typ SDK desky: bílá; Object Layer Attributes #1, Způsob opláštění: Oboustranné; Object Layer Attributes #1, Tloušťka izolace (2): 50; Object Layer Attributes #1, Objemová hmotnost izolace: 25; Object Layer Attributes #1, Číslo místnosti: 1.01a; Object Layer Attributes #1, Hmotnost (2): 65 kg
SDK - OCEL. KCE + 2 OPLÁŠTĚNÍ | Půdorys 1.NP | SDK - OCEL. KCE + 2 OPLÁŠTĚNÍ 0.1 m |  | SDK - OCEL. KCE + 2 OPLÁŠTĚNÍ |  | 1464HWa1096238173 | m3 | Celá stěna | Nový | Suché stavební práce | SDK - OCEL. KCE + 2 OPLÁŠTĚNÍ | no | 1464Stě1096238174 | m3 | Stěna |  | 0.1 | 2.28 | 2.099 | 0.228 | 3.8 | 0.21 | 0.38 | 0.6 | NEMSOK - Object Layer Attributes #1, Kód prvku: ZV00.03.2001; Object Layer Attributes #1, Podlaží: 1.NP; Object Layer Attributes #1, Požární odolnost: bez požadavku; Object Layer Attributes #1, Funkce (venkovní): Ne; Object Layer Attributes #1, Vlhkostní namáhání oboustranné: Ne; Object Layer Attributes #1, Tloušťka opláštění: 2×12,5; Object Layer Attributes #1, Typ SDK desky: bílá; Object Layer Attributes #1, Způsob opláštění: Oboustranné; Object Layer Attributes #1, Tloušťka izolace (2): 50; Object Layer Attributes #1, Objemová hmotnost izolace: 25; Object Layer Attributes #1, Číslo místnosti: 1.08; Object Layer Attributes #1, Hmotnost (2): 40 kg
SDK - OCEL. KCE + 2 OPLÁŠTĚNÍ | Půdorys 1.NP | SDK - OCEL. KCE + 2 OPLÁŠTĚNÍ 0.1 m |  | SDK - OCEL. KCE + 2 OPLÁŠTĚNÍ |  | 1464HWa1096238180 | m3 | Celá stěna | Nový | Suché stavební práce | SDK - OCEL. KCE + 2 OPLÁŠTĚNÍ | no | 1464Stě1096238181 | m3 | Stěna |  | 0.1 | 2.01 | 1.896 | 0.201 | 3.35 | 0.19 | 0.335 | 0.6 | NEMSOK - Object Layer Attributes #1, Kód prvku: ZV00.03.2001; Object Layer Attributes #1, Podlaží: 1.NP; Object Layer Attributes #1, Požární odolnost: bez požadavku; Object Layer Attributes #1, Funkce (venkovní): Ne; Object Layer Attributes #1, Vlhkostní namáhání oboustranné: Ne; Object Layer Attributes #1, Tloušťka opláštění: 2×12,5; Object Layer Attributes #1, Typ SDK desky: bílá; Object Layer Attributes #1, Způsob opláštění: Oboustranné; Object Layer Attributes #1, Tloušťka izolace (2): 50; Object Layer Attributes #1, Objemová hmotnost izolace: 25; Object Layer Attributes #1, Číslo místnosti: 1.10; Object Layer Attributes #1, Hmotnost (2): 40 kg
SDK - OCEL. KCE + 2 OPLÁŠTĚNÍ | Půdorys 1.NP | SDK - OCEL. KCE + 2 OPLÁŠTĚNÍ 0.1 m |  | SDK - OCEL. KCE + 2 OPLÁŠTĚNÍ |  | 1464HWa1096238186 | m3 | Celá stěna | Nový | Suché stavební práce | SDK - OCEL. KCE + 2 OPLÁŠTĚNÍ | no | 1464Stě1096238187 | m3 | Stěna |  | 0.1 | 9.76 | 9.561 | 0.976 | 16.267 | 0.956 | 1.627 | 0.6 | NEMSOK - Object Layer Attributes #1, Kód prvku: ZV00.03.2001; Object Layer Attributes #1, Podlaží: 1.NP; Object Layer Attributes #1, Požární odolnost: bez požadavku; Object Layer Attributes #1, Funkce (venkovní): Ne; Object Layer Attributes #1, Vlhkostní namáhání oboustranné: Ne; Object Layer Attributes #1, Tloušťka opláštění: 2×12,5; Object Layer Attributes #1, Typ SDK desky: bílá; Object Layer Attributes #1, Způsob opláštění: Oboustranné; Object Layer Attributes #1, Tloušťka izolace (2): 50; Object Layer Attributes #1, Objemová hmotnost izolace: 25; Object Layer Attributes #1, Číslo místnosti: 1.08; Object Layer Attributes #1, Hmotnost (2): 150 kg
SDK - OCEL. KCE + 2 OPLÁŠTĚNÍ | Půdorys 1.NP | SDK - OCEL. KCE + 2 OPLÁŠTĚNÍ 0.1 m |  | SDK - OCEL. KCE + 2 OPLÁŠTĚNÍ |  | 1464HWa1096238193 | m3 | Celá stěna | Nový | Suché stavební práce | SDK - OCEL. KCE + 2 OPLÁŠTĚNÍ | no | 1464Stě1096238194 | m3 | Stěna |  | 0.1 | 1.003 | 1.004 | 0.1 | 1.671 | 0.1 | 0.167 | 0.6 | NEMSOK - Object Layer Attributes #1, Kód prvku: ZV00.03.2001; Object Layer Attributes #1, Podlaží: 1.NP; Object Layer Attributes #1, Požární odolnost: bez požadavku; Object Layer Attributes #1, Funkce (venkovní): Ne; Object Layer Attributes #1, Vlhkostní namáhání oboustranné: Ne; Object Layer Attributes #1, Tloušťka opláštění: 2×12,5; Object Layer Attributes #1, Typ SDK desky: bílá; Object Layer Attributes #1, Způsob opláštění: Oboustranné; Object Layer Attributes #1, Tloušťka izolace (2): 50; Object Layer Attributes #1, Objemová hmotnost izolace: 25; Object Layer Attributes #1, Číslo místnosti: 1.15; Object Layer Attributes #1, Hmotnost (2): 20 kg
SDK - OCEL. KCE + 2 OPLÁŠTĚNÍ | Půdorys 1.NP | SDK - OCEL. KCE + 2 OPLÁŠTĚNÍ 0.1 m |  | SDK - OCEL. KCE + 2 OPLÁŠTĚNÍ |  | 1464HWa1096238204 | m3 | Celá stěna | Nový | Suché stavební práce | SDK - OCEL. KCE + 2 OPLÁŠTĚNÍ | no | 1464Stě1096238205 | m3 | Stěna |  | 0.1 | 1.51 | 1.417 | 0.151 | 2.517 | 0.142 | 0.252 | 0.6 | NEMSOK - Object Layer Attributes #1, Kód prvku: ZV00.03.2001; Object Layer Attributes #1, Podlaží: 1.NP; Object Layer Attributes #1, Požární odolnost: bez požadavku; Object Layer Attributes #1, Funkce (venkovní): Ne; Object Layer Attributes #1, Vlhkostní namáhání oboustranné: Ne; Object Layer Attributes #1, Tloušťka opláštění: 2×12,5; Object Layer Attributes #1, Typ SDK desky: bílá; Object Layer Attributes #1, Způsob opláštění: Oboustranné; Object Layer Attributes #1, Tloušťka izolace (2): 50; Object Layer Attributes #1, Objemová hmotnost izolace: 25; Object Layer Attributes #1, Číslo místnosti: 1.15; Object Layer Attributes #1, Hmotnost (2): 26 kg
SDK - OCEL. KCE + 2 OPLÁŠTĚNÍ | Půdorys 1.NP | SDK - OCEL. KCE + 2 OPLÁŠTĚNÍ 0.1 m |  | SDK - OCEL. KCE + 2 OPLÁŠTĚNÍ |  | 1464HWa1096238217 | m3 | Celá stěna | Nový | Suché stavební práce | SDK - OCEL. KCE + 2 OPLÁŠTĚNÍ | no | 1464Stě1096238218 | m3 | Stěna |  | 0.1 | 2.19 | 2.097 | 0.219 | 3.65 | 0.21 | 0.365 | 0.6 | NEMSOK - Object Layer Attributes #1, Kód prvku: ZV00.03.2001; Object Layer Attributes #1, Podlaží: 1.NP; Object Layer Attributes #1, Požární odolnost: bez požadavku; Object Layer Attributes #1, Funkce (venkovní): Ne; Object Layer Attributes #1, Vlhkostní namáhání oboustranné: Ne; Object Layer Attributes #1, Tloušťka opláštění: 2×12,5; Object Layer Attributes #1, Typ SDK desky: bílá; Object Layer Attributes #1, Způsob opláštění: Oboustranné; Object Layer Attributes #1, Tloušťka izolace (2): 50; Object Layer Attributes #1, Objemová hmotnost izolace: 25; Object Layer Attributes #1, Číslo místnosti: 1.14; Object Layer Attributes #1, Hmotnost (2): 40 kg
SDK - OCEL. KCE + 2 OPLÁŠTĚNÍ | Půdorys 1.NP | SDK - OCEL. KCE + 2 OPLÁŠTĚNÍ 0.1 m |  | SDK - OCEL. KCE + 2 OPLÁŠTĚNÍ |  | 1464HWa1096238226 | m3 | Celá stěna | Nový | Suché stavební práce | SDK - OCEL. KCE + 2 OPLÁŠTĚNÍ | no | 1464Stě1096238227 | m3 | Stěna |  | 0.1 | 2.19 | 2.085 | 0.219 | 3.65 | 0.209 | 0.365 | 0.6 | NEMSOK - Object Layer Attributes #1, Kód prvku: ZV00.03.2001; Object Layer Attributes #1, Podlaží: 1.NP; Object Layer Attributes #1, Požární odolnost: bez požadavku; Object Layer Attributes #1, Funkce (venkovní): Ne; Object Layer Attributes #1, Vlhkostní namáhání oboustranné: Ne; Object Layer Attributes #1, Tloušťka opláštění: 2×12,5; Object Layer Attributes #1, Typ SDK desky: bílá; Object Layer Attributes #1, Způsob opláštění: Oboustranné; Object Layer Attributes #1, Tloušťka izolace (2): 50; Object Layer Attributes #1, Objemová hmotnost izolace: 25; Object Layer Attributes #1, Číslo místnosti: 1.13; Object Layer Attributes #1, Hmotnost (2): 40 kg
SDK - OCEL. KCE + 2 OPLÁŠTĚNÍ | Půdorys 1.NP | SDK - OCEL. KCE + 2 OPLÁŠTĚNÍ 0.1 m |  | SDK - OCEL. KCE + 2 OPLÁŠTĚNÍ |  | 1464HWa1096238244 | m3 | Celá stěna | Nový | Suché stavební práce | SDK - OCEL. KCE + 2 OPLÁŠTĚNÍ | no | 1464Stě1096238245 | m3 | Stěna |  | 0.1 | 2.19 | 2.085 | 0.219 | 3.65 | 0.209 | 0.365 | 0.6 | NEMSOK - Object Layer Attributes #1, Kód prvku: ZV00.03.2001; Object Layer Attributes #1, Podlaží: 1.NP; Object Layer Attributes #1, Požární odolnost: bez požadavku; Object Layer Attributes #1, Funkce (venkovní): Ne; Object Layer Attributes #1, Vlhkostní namáhání oboustranné: Ne; Object Layer Attributes #1, Tloušťka opláštění: 2×12,5; Object Layer Attributes #1, Typ SDK desky: bílá; Object Layer Attributes #1, Způsob opláštění: Oboustranné; Object Layer Attributes #1, Tloušťka izolace (2): 50; Object Layer Attributes #1, Objemová hmotnost izolace: 25; Object Layer Attributes #1, Číslo místnosti: 1.12; Object Layer Attributes #1, Hmotnost (2): 40 kg
SDK - OCEL. KCE + 2 OPLÁŠTĚNÍ | Půdorys 1.NP | SDK - OCEL. KCE + 2 OPLÁŠTĚNÍ 0.1 m |  | SDK - OCEL. KCE + 2 OPLÁŠTĚNÍ |  | 1464HWa1096238257 | m3 | Celá stěna | Nový | Suché stavební práce | SDK - OCEL. KCE + 2 OPLÁŠTĚNÍ | no | 1464Stě1096238259 | m3 | Stěna |  | 0.1 | 2.19 | 2.076 | 0.219 | 3.65 | 0.208 | 0.365 | 0.6 | NEMSOK - Object Layer Attributes #1, Kód prvku: ZV00.03.2001; Object Layer Attributes #1, Podlaží: 1.NP; Object Layer Attributes #1, Požární odolnost: bez požadavku; Object Layer Attributes #1, Funkce (venkovní): Ne; Object Layer Attributes #1, Vlhkostní namáhání oboustranné: Ne; Object Layer Attributes #1, Tloušťka opláštění: 2×12,5; Object Layer Attributes #1, Typ SDK desky: bílá; Object Layer Attributes #1, Způsob opláštění: Oboustranné; Object Layer Attributes #1, Tloušťka izolace (2): 50; Object Layer Attributes #1, Objemová hmotnost izolace: 25; Object Layer Attributes #1, Číslo místnosti: 1.11; Object Layer Attributes #1, Hmotnost (2): 40 kg
SDK - OCEL. KCE + 2 OPLÁŠTĚNÍ | Půdorys 1.NP | SDK - OCEL. KCE + 2 OPLÁŠTĚNÍ 0.1 m |  | SDK - OCEL. KCE + 2 OPLÁŠTĚNÍ |  | 1464HWa1096238318 | m3 | Celá stěna | Nový | Suché stavební práce | SDK - OCEL. KCE + 2 OPLÁŠTĚNÍ | no | 1464Stě1096238319 | m3 | Stěna |  | 0.1 | 1.018 | 0.823 | 0.102 | 1.697 | 0.082 | 0.17 | 0.6 | NEMSOK - Object Layer Attributes #1, Kód prvku: ZV00.03.2001; Object Layer Attributes #1, Podlaží: 1.NP; Object Layer Attributes #1, Požární odolnost: bez požadavku; Object Layer Attributes #1, Funkce (venkovní): Ne; Object Layer Attributes #1, Vlhkostní namáhání oboustranné: Ne; Object Layer Attributes #1, Tloušťka opláštění: 2×12,5; Object Layer Attributes #1, Typ SDK desky: bílá; Object Layer Attributes #1, Způsob opláštění: Oboustranné; Object Layer Attributes #1, Tloušťka izolace (2): 50; Object Layer Attributes #1, Objemová hmotnost izolace: 25; Object Layer Attributes #1, Číslo místnosti: 1.08; Object Layer Attributes #1, Hmotnost (2): 20 kg
SDK - 1 KCE + DVOJITÉ OPLÁŠTĚNÍ | Půdorys 1.NP | SDK - 1 KCE + DVOJITÉ OPLÁŠTĚNÍ 0.125 m |  | SDK - 1 KCE + DVOJITÉ OPLÁŠTĚNÍ |  | 1464HWa1096312733 | m3 | Celá stěna | Nový | Suché stavební práce | SDK - 1 KCE + DVOJITÉ OPLÁŠTĚNÍ | no | 1464Stě1096314574 | m3 | Stěna |  | 0.125 | 14.74 | 10.73 | 1.843 | 4.4 | 1.341 | 0.55 | 3.35 | NEMSOK - Object Layer Attributes #1, Kód prvku: SN07.03.0001; Object Layer Attributes #1, Podlaží: 1.NP; Object Layer Attributes #1, Požární odolnost: EI 60; Object Layer Attributes #1, Funkce (venkovní): Ne; Object Layer Attributes #1, Statická funkce: Ne; Object Layer Attributes #1, Vážená stavební neprůzvučnost: 54; Object Layer Attributes #1, Vlhkostní namáhání oboustranné: Ne; Object Layer Attributes #1, Tloušťka opláštění: 2×12,5; Object Layer Attributes #1, Typ SDK desky: vysokopevnostní+bílá; Object Layer Attributes #1, Způsob opláštění: Oboustranné; Object Layer Attributes #1, Tloušťka izolace (2): 75; Object Layer Attributes #1, Objemová hmotnost izolace: 25; Object Layer Attributes #1, Typ profilu pro SDK: CW 75; Object Layer Attributes #1, Rozteč rastru: 625
SDK - 1 KCE + DVOJITÉ OPLÁŠTĚNÍ | Půdorys 1.NP | SDK - 1 KCE + DVOJITÉ OPLÁŠTĚNÍ 0.15 m |  | SDK - 1 KCE + DVOJITÉ OPLÁŠTĚNÍ |  | 1464HWa1096312735 | m3 | Celá stěna | Nový | Suché stavební práce | SDK - 1 KCE + DVOJITÉ OPLÁŠTĚNÍ | no | 1464Stě1096313135 | m3 | Stěna |  | 0.15 | 5.109 | 5.109 | 0.766 | 1.525 | 0.766 | 0.229 | 3.35 | NEMSOK - Object Layer Attributes #1, Kód prvku: SN07.03.0001; Object Layer Attributes #1, Podlaží: 1.NP; Object Layer Attributes #1, Požární odolnost: EI 60; Object Layer Attributes #1, Funkce (venkovní): Ne; Object Layer Attributes #1, Statická funkce: Ne; Object Layer Attributes #1, Vážená stavební neprůzvučnost: 54; Object Layer Attributes #1, Vlhkostní namáhání oboustranné: Ne; Object Layer Attributes #1, Tloušťka opláštění: 2×12,5; Object Layer Attributes #1, Typ SDK desky: vysokopevnostní+bílá; Object Layer Attributes #1, Způsob opláštění: Oboustranné; Object Layer Attributes #1, Tloušťka izolace (2): 100; Object Layer Attributes #1, Objemová hmotnost izolace: 25; Object Layer Attributes #1, Typ profilu pro SDK: CW 100; Object Layer Attributes #1, Rozteč rastru: 625
SDK - 2 KCE + DVOJITÉ OPLÁŠTĚNÍ | Půdorys 1.NP | SDK - 2 KCE + DVOJITÉ OPLÁŠTĚNÍ 0.25 m |  | SDK - 2 KCE + DVOJITÉ OPLÁŠTĚNÍ |  | 1464HWa1096312736 | m3 | Celá stěna | Nový | Suché stavební práce | SDK - 2 KCE + DVOJITÉ OPLÁŠTĚNÍ | no | 1464Stě1096313513 | m3 | Stěna |  | 0.25 | 4.104 | 4.104 | 1.026 | 1.225 | 1.024 | 0.306 | 3.35 | NEMSOK - Object Layer Attributes #1, Kód prvku: SN07.03.0001; Object Layer Attributes #1, Podlaží: 1.NP; Object Layer Attributes #1, Požární odolnost: EI 60; Object Layer Attributes #1, Funkce (venkovní): Ne; Object Layer Attributes #1, Statická funkce: Ne; Object Layer Attributes #1, Vážená stavební neprůzvučnost: 54; Object Layer Attributes #1, Vlhkostní namáhání oboustranné: Ne; Object Layer Attributes #1, Tloušťka opláštění: 2×12,5; Object Layer Attributes #1, Typ SDK desky: vysokopevnostní+bílá; Object Layer Attributes #1, Způsob opláštění: Oboustranné; Object Layer Attributes #1, Tloušťka izolace (2): 100; Object Layer Attributes #1, Objemová hmotnost izolace: 25; Object Layer Attributes #1, Typ profilu pro SDK: 2× CW 100; Object Layer Attributes #1, Rozteč rastru: 625
SDK - 1 KCE + DVOJITÉ OPLÁŠTĚNÍ | Půdorys 1.NP | SDK - 1 KCE + DVOJITÉ OPLÁŠTĚNÍ 0.125 m |  | SDK - 1 KCE + DVOJITÉ OPLÁŠTĚNÍ |  | 1464HWa1096312737 | m3 | Celá stěna | Nový | Suché stavební práce | SDK - 1 KCE + DVOJITÉ OPLÁŠTĚNÍ | no | 1464Stě1096313140 | m3 | Stěna |  | 0.125 | 8.71 | 8.71 | 1.089 | 2.6 | 1.089 | 0.325 | 3.35 | NEMSOK - Object Layer Attributes #1, Kód prvku: SN07.03.0001; Object Layer Attributes #1, Podlaží: 1.NP; Object Layer Attributes #1, Požární odolnost: EI 60; Object Layer Attributes #1, Funkce (venkovní): Ne; Object Layer Attributes #1, Statická funkce: Ne; Object Layer Attributes #1, Vážená stavební neprůzvučnost: 54; Object Layer Attributes #1, Vlhkostní namáhání oboustranné: Ne; Object Layer Attributes #1, Tloušťka opláštění: 2×12,5; Object Layer Attributes #1, Typ SDK desky: vysokopevnostní+bílá; Object Layer Attributes #1, Způsob opláštění: Oboustranné; Object Layer Attributes #1, Tloušťka izolace (2): 75; Object Layer Attributes #1, Objemová hmotnost izolace: 25; Object Layer Attributes #1, Typ profilu pro SDK: CW 75; Object Layer Attributes #1, Rozteč rastru: 625
SDK - 1 KCE + DVOJITÉ OPLÁŠTĚNÍ | Půdorys 1.NP | SDK - 1 KCE + DVOJITÉ OPLÁŠTĚNÍ 0.125 m |  | SDK - 1 KCE + DVOJITÉ OPLÁŠTĚNÍ |  | 1464HWa1096312738 | m3 | Celá stěna | Nový | Suché stavební práce | SDK - 1 KCE + DVOJITÉ OPLÁŠTĚNÍ | no | 1464Stě1096313146 | m3 | Stěna |  | 0.125 | 8.375 | 8.375 | 1.047 | 2.5 | 1.047 | 0.313 | 3.35 | NEMSOK - Object Layer Attributes #1, Kód prvku: SN07.03.0001; Object Layer Attributes #1, Podlaží: 1.NP; Object Layer Attributes #1, Požární odolnost: EI 60; Object Layer Attributes #1, Funkce (venkovní): Ne; Object Layer Attributes #1, Statická funkce: Ne; Object Layer Attributes #1, Vážená stavební neprůzvučnost: 54; Object Layer Attributes #1, Vlhkostní namáhání oboustranné: Ne; Object Layer Attributes #1, Tloušťka opláštění: 2×12,5; Object Layer Attributes #1, Typ SDK desky: vysokopevnostní+bílá; Object Layer Attributes #1, Způsob opláštění: Oboustranné; Object Layer Attributes #1, Tloušťka izolace (2): 75; Object Layer Attributes #1, Objemová hmotnost izolace: 25; Object Layer Attributes #1, Typ profilu pro SDK: CW 75; Object Layer Attributes #1, Rozteč rastru: 625
SDK - 1 KCE + DVOJITÉ OPLÁŠTĚNÍ | Půdorys 1.NP | SDK - 1 KCE + DVOJITÉ OPLÁŠTĚNÍ 0.1 m |  | SDK - 1 KCE + DVOJITÉ OPLÁŠTĚNÍ |  | 1464HWa1096312743 | m3 | Celá stěna | Nový | Suché stavební práce | SDK - 1 KCE + DVOJITÉ OPLÁŠTĚNÍ | no | 1464Stě1096314631 | m3 | Stěna |  | 0.1 | 5.276 | 3.395 | 0.528 | 1.575 | 0.34 | 0.157 | 3.35 | NEMSOK - Object Layer Attributes #1, Kód prvku: SN07.03.0001; Object Layer Attributes #1, Podlaží: 1.NP; Object Layer Attributes #1, Požární odolnost: EI 60; Object Layer Attributes #1, Funkce (venkovní): Ne; Object Layer Attributes #1, Statická funkce: Ne; Object Layer Attributes #1, Vážená stavební neprůzvučnost: 54; Object Layer Attributes #1, Vlhkostní namáhání oboustranné: Ne; Object Layer Attributes #1, Tloušťka opláštění: 2×12,5; Object Layer Attributes #1, Typ SDK desky: vysokopevnostní+bílá; Object Layer Attributes #1, Způsob opláštění: Oboustranné; Object Layer Attributes #1, Tloušťka izolace (2): 50; Object Layer Attributes #1, Objemová hmotnost izolace: 25; Object Layer Attributes #1, Typ profilu pro SDK: CW 50; Object Layer Attributes #1, Rozteč rastru: 625
SDK - 1 KCE + DVOJITÉ OPLÁŠTĚNÍ | Půdorys 1.NP | SDK - 1 KCE + DVOJITÉ OPLÁŠTĚNÍ 0.125 m |  | SDK - 1 KCE + DVOJITÉ OPLÁŠTĚNÍ |  | 1464HWa1096312745 | m3 | Celá stěna | Nový | Suché stavební práce | SDK - 1 KCE + DVOJITÉ OPLÁŠTĚNÍ | no | 1464Stě1096314663 | m3 | Stěna |  | 0.125 | 12.144 | 7.959 | 1.518 | 3.625 | 0.995 | 0.453 | 3.35 | NEMSOK - Object Layer Attributes #1, Kód prvku: SN07.03.0001; Object Layer Attributes #1, Podlaží: 1.NP; Object Layer Attributes #1, Požární odolnost: EI 60; Object Layer Attributes #1, Funkce (venkovní): Ne; Object Layer Attributes #1, Statická funkce: Ne; Object Layer Attributes #1, Vážená stavební neprůzvučnost: 54; Object Layer Attributes #1, Vlhkostní namáhání oboustranné: Ne; Object Layer Attributes #1, Tloušťka opláštění: 2×12,5; Object Layer Attributes #1, Typ SDK desky: vysokopevnostní+bílá; Object Layer Attributes #1, Způsob opláštění: Oboustranné; Object Layer Attributes #1, Tloušťka izolace (2): 75; Object Layer Attributes #1, Objemová hmotnost izolace: 25; Object Layer Attributes #1, Typ profilu pro SDK: CW 75; Object Layer Attributes #1, Rozteč rastru: 625
SDK - 1 KCE + DVOJITÉ OPLÁŠTĚNÍ | Půdorys 1.NP | SDK - 1 KCE + DVOJITÉ OPLÁŠTĚNÍ 0.125 m |  | SDK - 1 KCE + DVOJITÉ OPLÁŠTĚNÍ |  | 1464HWa1096312748 | m3 | Celá stěna | Nový | Suché stavební práce | SDK - 1 KCE + DVOJITÉ OPLÁŠTĚNÍ | no | 1464Stě1096313144 | m3 | Stěna |  | 0.125 | 7.537 | 5.513 | 0.942 | 2.25 | 0.689 | 0.281 | 3.35 | NEMSOK - Object Layer Attributes #1, Kód prvku: SN07.03.0001; Object Layer Attributes #1, Podlaží: 1.NP; Object Layer Attributes #1, Požární odolnost: EI 60; Object Layer Attributes #1, Funkce (venkovní): Ne; Object Layer Attributes #1, Statická funkce: Ne; Object Layer Attributes #1, Vážená stavební neprůzvučnost: 54; Object Layer Attributes #1, Vlhkostní namáhání oboustranné: Ne; Object Layer Attributes #1, Tloušťka opláštění: 2×12,5; Object Layer Attributes #1, Typ SDK desky: vysokopevnostní+bílá; Object Layer Attributes #1, Způsob opláštění: Oboustranné; Object Layer Attributes #1, Tloušťka izolace (2): 75; Object Layer Attributes #1, Objemová hmotnost izolace: 25; Object Layer Attributes #1, Typ profilu pro SDK: CW 75; Object Layer Attributes #1, Rozteč rastru: 625
SDK INSTAL. PŘDSTĚNA VYSOKÁ | Půdorys 1.NP | SDK INSTAL. PŘDSTĚNA VYSOKÁ 0.2 m |  | SDK INSTAL. PŘDSTĚNA VYSOKÁ |  | 1464HWa1096312751 | m3 | Celá stěna | Nový | Suché stavební práce | SDK INSTAL. PŘDSTĚNA VYSOKÁ | no | 1464Stě1096313523 | m3 | Stěna |  | 0.2 | 4.225 | 4.062 | 0.845 | 1.3 | 0.81 | 0.26 | 3.25 | NEMSOK - Object Layer Attributes #1, Kód prvku: SN07.03.0001; Object Layer Attributes #1, Podlaží: 1.NP; Object Layer Attributes #1, Požární odolnost: bez požadavku; Object Layer Attributes #1, Funkce (venkovní): Ne; Object Layer Attributes #1, Statická funkce: Ne; Object Layer Attributes #1, Vlhkostní namáhání oboustranné: Ne; Object Layer Attributes #1, Tloušťka opláštění: 2×12,5; Object Layer Attributes #1, Typ SDK desky: impregnovaná; Object Layer Attributes #1, Způsob opláštění: Jednostranné; Object Layer Attributes #1, Tloušťka izolace (2): 0; Object Layer Attributes #1, Objemová hmotnost izolace: 0; Object Layer Attributes #1, Typ profilu pro SDK: CW 100; Object Layer Attributes #1, Rozteč rastru: 625
SDK OPL. PROFESÍ/SDK OPL. BEZ PO | Půdorys 1.NP | SDK OPL. PROFESÍ/SDK OPL. BEZ PO 0.075 m |  | SDK OPL. PROFESÍ/SDK OPL. BEZ PO |  | 1464HWa1096312753 | m3 | Celá stěna | Nový | Suché stavební práce | SDK OPL. PROFESÍ/SDK OPL. BEZ PO | no | 1464Stě1096314480 | m3 | Stěna |  | 0.075 | 5.688 | 5.688 | 0.427 | 1.75 | 0.427 | 0.131 | 3.25 | NEMSOK - Object Layer Attributes #1, Kód prvku: SN07.03.0001; Object Layer Attributes #1, Podlaží: 1.NP; Object Layer Attributes #1, Požární odolnost: bez požadavku; Object Layer Attributes #1, Funkce (venkovní): Ne; Object Layer Attributes #1, Statická funkce: Ne; Object Layer Attributes #1, Vlhkostní namáhání oboustranné: Ne; Object Layer Attributes #1, Tloušťka opláštění: 2×12,5; Object Layer Attributes #1, Typ SDK desky: vysokopevnostní+bílá; Object Layer Attributes #1, Způsob opláštění: Jednostranné; Object Layer Attributes #1, Tloušťka izolace (2): 0; Object Layer Attributes #1, Objemová hmotnost izolace: 0; Object Layer Attributes #1, Typ profilu pro SDK: CW 100; Object Layer Attributes #1, Rozteč rastru: 625
SDK OPL. PROFESÍ/SDK OPL. BEZ PO | Půdorys 1.NP | SDK OPL. PROFESÍ/SDK OPL. BEZ PO 0.075 m |  | SDK OPL. PROFESÍ/SDK OPL. BEZ PO |  | 1464HWa1096312754 | m3 | Celá stěna | Nový | Suché stavební práce | SDK OPL. PROFESÍ/SDK OPL. BEZ PO | no | 1464Stě1096314482 | m3 | Stěna |  | 0.075 | 4.794 | 4.794 | 0.36 | 1.475 | 0.36 | 0.111 | 3.25 | NEMSOK - Object Layer Attributes #1, Kód prvku: SN07.03.0001; Object Layer Attributes #1, Podlaží: 1.NP; Object Layer Attributes #1, Požární odolnost: bez požadavku; Object Layer Attributes #1, Funkce (venkovní): Ne; Object Layer Attributes #1, Statická funkce: Ne; Object Layer Attributes #1, Vlhkostní namáhání oboustranné: Ne; Object Layer Attributes #1, Tloušťka opláštění: 2×12,5; Object Layer Attributes #1, Typ SDK desky: vysokopevnostní+bílá; Object Layer Attributes #1, Způsob opláštění: Jednostranné; Object Layer Attributes #1, Tloušťka izolace (2): 0; Object Layer Attributes #1, Objemová hmotnost izolace: 0; Object Layer Attributes #1, Typ profilu pro SDK: CW 100; Object Layer Attributes #1, Rozteč rastru: 625
SDK - 1 KCE + DVOJITÉ OPLÁŠTĚNÍ | Půdorys 1.NP | SDK - 1 KCE + DVOJITÉ OPLÁŠTĚNÍ 0.125 m |  | SDK - 1 KCE + DVOJITÉ OPLÁŠTĚNÍ |  | 1464HWa1096312764 | m3 | Celá stěna | Nový | Suché stavební práce | SDK - 1 KCE + DVOJITÉ OPLÁŠTĚNÍ | no | 1464Stě1096314049 | m3 | Stěna |  | 0.125 | 10.553 | 10.522 | 1.319 | 3.15 | 1.315 | 0.394 | 3.35 | NEMSOK - Object Layer Attributes #1, Kód prvku: SN07.03.0001; Object Layer Attributes #1, Podlaží: 1.NP; Object Layer Attributes #1, Požární odolnost: EI 60; Object Layer Attributes #1, Funkce (venkovní): Ne; Object Layer Attributes #1, Statická funkce: Ne; Object Layer Attributes #1, Vážená stavební neprůzvučnost: 54; Object Layer Attributes #1, Vlhkostní namáhání oboustranné: Ne; Object Layer Attributes #1, Tloušťka opláštění: 2×12,5; Object Layer Attributes #1, Typ SDK desky: vysokopevnostní+bílá; Object Layer Attributes #1, Způsob opláštění: Oboustranné; Object Layer Attributes #1, Tloušťka izolace (2): 75; Object Layer Attributes #1, Objemová hmotnost izolace: 25; Object Layer Attributes #1, Typ profilu pro SDK: CW 75; Object Layer Attributes #1, Rozteč rastru: 625
SDK - 1 KCE + DVOJITÉ OPLÁŠTĚNÍ | Půdorys 1.NP | SDK - 1 KCE + DVOJITÉ OPLÁŠTĚNÍ 0.125 m |  | SDK - 1 KCE + DVOJITÉ OPLÁŠTĚNÍ |  | 1464HWa1096312765 | m3 | Celá stěna | Nový | Suché stavební práce | SDK - 1 KCE + DVOJITÉ OPLÁŠTĚNÍ | no | 1464Stě1096312792 | m3 | Stěna |  | 0.125 | 18.09 | 18.09 | 2.261 | 5.4 | 2.261 | 0.675 | 3.35 | NEMSOK - Object Layer Attributes #1, Kód prvku: SN07.03.0001; Object Layer Attributes #1, Podlaží: 1.NP; Object Layer Attributes #1, Požární odolnost: EI 60; Object Layer Attributes #1, Funkce (venkovní): Ne; Object Layer Attributes #1, Statická funkce: Ne; Object Layer Attributes #1, Vážená stavební neprůzvučnost: 54; Object Layer Attributes #1, Vlhkostní namáhání oboustranné: Ne; Object Layer Attributes #1, Tloušťka opláštění: 2×12,5; Object Layer Attributes #1, Typ SDK desky: vysokopevnostní+bílá; Object Layer Attributes #1, Způsob opláštění: Oboustranné; Object Layer Attributes #1, Tloušťka izolace (2): 75; Object Layer Attributes #1, Objemová hmotnost izolace: 25; Object Layer Attributes #1, Typ profilu pro SDK: CW 75; Object Layer Attributes #1, Rozteč rastru: 625
SDK - 1 KCE + DVOJITÉ OPLÁŠTĚNÍ | Půdorys 1.NP | SDK - 1 KCE + DVOJITÉ OPLÁŠTĚNÍ 0.125 m |  | SDK - 1 KCE + DVOJITÉ OPLÁŠTĚNÍ |  | 1464HWa1096312773 | m3 | Celá stěna | Nový | Suché stavební práce | SDK - 1 KCE + DVOJITÉ OPLÁŠTĚNÍ | no | 1464Stě1096313855 | m3 | Stěna |  | 0.125 | 17.169 | 14.417 | 2.146 | 5.125 | 1.802 | 0.641 | 3.35 | NEMSOK - Object Layer Attributes #1, Kód prvku: SN07.03.0001; Object Layer Attributes #1, Podlaží: 1.NP; Object Layer Attributes #1, Požární odolnost: EI 60; Object Layer Attributes #1, Funkce (venkovní): Ne; Object Layer Attributes #1, Statická funkce: Ne; Object Layer Attributes #1, Vážená stavební neprůzvučnost: 54; Object Layer Attributes #1, Vlhkostní namáhání oboustranné: Ne; Object Layer Attributes #1, Tloušťka opláštění: 2×12,5; Object Layer Attributes #1, Typ SDK desky: vysokopevnostní+bílá; Object Layer Attributes #1, Způsob opláštění: Oboustranné; Object Layer Attributes #1, Tloušťka izolace (2): 75; Object Layer Attributes #1, Objemová hmotnost izolace: 25; Object Layer Attributes #1, Typ profilu pro SDK: CW 75; Object Layer Attributes #1, Rozteč rastru: 625
SDK ŠACHTOVÁ STĚNA/SDK OPL. S PO | Půdorys 1.NP | SDK ŠACHTOVÁ STĚNA/SDK OPL. S PO 0.075 m |  | SDK ŠACHTOVÁ STĚNA/SDK OPL. S PO |  | 1464HWa1096312774 | m3 | Celá stěna | Nový | Suché stavební práce | SDK ŠACHTOVÁ STĚNA/SDK OPL. S PO | no | 1464Stě1096312858 | m3 | Stěna |  | 0.075 | 1.256 | 1.256 | 0.094 | 0.375 | 0.094 | 0.028 | 3.35 | NEMSOK - Object Layer Attributes #1, Kód prvku: SN07.03.0001; Object Layer Attributes #1, Podlaží: 1.NP; Object Layer Attributes #1, Požární odolnost: bez požadavku; Object Layer Attributes #1, Funkce (venkovní): Ne; Object Layer Attributes #1, Statická funkce: Ne; Object Layer Attributes #1, Vlhkostní namáhání oboustranné: Ne; Object Layer Attributes #1, Tloušťka opláštění: 2×12,5; Object Layer Attributes #1, Typ SDK desky: vysokopevnostní+bílá; Object Layer Attributes #1, Způsob opláštění: Jednostranné; Object Layer Attributes #1, Tloušťka izolace (2): 0; Object Layer Attributes #1, Objemová hmotnost izolace: 0; Object Layer Attributes #1, Typ profilu pro SDK: CW 100; Object Layer Attributes #1, Rozteč rastru: 625
SDK ŠACHTOVÁ STĚNA/SDK OPL. S PO | Půdorys 1.NP | SDK ŠACHTOVÁ STĚNA/SDK OPL. S PO 0.075 m |  | SDK ŠACHTOVÁ STĚNA/SDK OPL. S PO |  | 1464HWa1096312776 | m3 | Celá stěna | Nový | Suché stavební práce | SDK ŠACHTOVÁ STĚNA/SDK OPL. S PO | no | 1464Stě1096312845 | m3 | Stěna |  | 0.075 | 1.591 | 1.591 | 0.119 | 0.475 | 0.119 | 0.036 | 3.35 | NEMSOK - Object Layer Attributes #1, Kód prvku: SN07.03.0001; Object Layer Attributes #1, Podlaží: 1.NP; Object Layer Attributes #1, Požární odolnost: bez požadavku; Object Layer Attributes #1, Funkce (venkovní): Ne; Object Layer Attributes #1, Statická funkce: Ne; Object Layer Attributes #1, Vlhkostní namáhání oboustranné: Ne; Object Layer Attributes #1, Tloušťka opláštění: 2×12,5; Object Layer Attributes #1, Typ SDK desky: vysokopevnostní+bílá; Object Layer Attributes #1, Způsob opláštění: Jednostranné; Object Layer Attributes #1, Tloušťka izolace (2): 0; Object Layer Attributes #1, Objemová hmotnost izolace: 0; Object Layer Attributes #1, Typ profilu pro SDK: CW 100; Object Layer Attributes #1, Rozteč rastru: 625
SDK - 1 KCE + DVOJITÉ OPLÁŠTĚNÍ | Půdorys 1.NP | SDK - 1 KCE + DVOJITÉ OPLÁŠTĚNÍ 0.1 m |  | SDK - 1 KCE + DVOJITÉ OPLÁŠTĚNÍ |  | 1464HWa1096312778 | m3 | Celá stěna | Nový | Suché stavební práce | SDK - 1 KCE + DVOJITÉ OPLÁŠTĚNÍ | no | 1464Stě1096314036 | m3 | Stěna |  | 0.1 | 7.035 | 5.308 | 0.704 | 2.1 | 0.531 | 0.21 | 3.35 | NEMSOK - Object Layer Attributes #1, Kód prvku: SN07.03.0001; Object Layer Attributes #1, Podlaží: 1.NP; Object Layer Attributes #1, Požární odolnost: EI 60; Object Layer Attributes #1, Funkce (venkovní): Ne; Object Layer Attributes #1, Statická funkce: Ne; Object Layer Attributes #1, Vážená stavební neprůzvučnost: 54; Object Layer Attributes #1, Vlhkostní namáhání oboustranné: Ne; Object Layer Attributes #1, Tloušťka opláštění: 2×12,5; Object Layer Attributes #1, Typ SDK desky: vysokopevnostní+bílá; Object Layer Attributes #1, Způsob opláštění: Oboustranné; Object Layer Attributes #1, Tloušťka izolace (2): 50; Object Layer Attributes #1, Objemová hmotnost izolace: 25; Object Layer Attributes #1, Typ profilu pro SDK: CW 50; Object Layer Attributes #1, Rozteč rastru: 625
SDK INSTAL. PŘDSTĚNA VYSOKÁ | Půdorys 1.NP | SDK INSTAL. PŘDSTĚNA VYSOKÁ 0.15 m |  | SDK INSTAL. PŘDSTĚNA VYSOKÁ |  | 1464HWa1096312782 | m3 | Celá stěna | Nový | Suché stavební práce | SDK INSTAL. PŘDSTĚNA VYSOKÁ | no | 1464Stě1096313039 | m3 | Stěna |  | 0.15 | 7.705 | 7.705 | 1.156 | 2.3 | 1.156 | 0.345 | 3.35 | NEMSOK - Object Layer Attributes #1, Kód prvku: SN07.03.0001; Object Layer Attributes #1, Podlaží: 1.NP; Object Layer Attributes #1, Požární odolnost: bez požadavku; Object Layer Attributes #1, Funkce (venkovní): Ne; Object Layer Attributes #1, Statická funkce: Ne; Object Layer Attributes #1, Vlhkostní namáhání oboustranné: Ne; Object Layer Attributes #1, Tloušťka opláštění: 2×12,5; Object Layer Attributes #1, Typ SDK desky: impregnovaná; Object Layer Attributes #1, Způsob opláštění: Jednostranné; Object Layer Attributes #1, Tloušťka izolace (2): 0; Object Layer Attributes #1, Objemová hmotnost izolace: 0; Object Layer Attributes #1, Typ profilu pro SDK: CW 100; Object Layer Attributes #1, Rozteč rastru: 625
SDK - 1 KCE + DVOJITÉ OPLÁŠTĚNÍ | Půdorys 1.NP | SDK - 1 KCE + DVOJITÉ OPLÁŠTĚNÍ 0.125 m |  | SDK - 1 KCE + DVOJITÉ OPLÁŠTĚNÍ |  | 1464HWa1096312784 | m3 | Celá stěna | Nový | Suché stavební práce | SDK - 1 KCE + DVOJITÉ OPLÁŠTĚNÍ | no | 1464Stě1096313831 | m3 | Stěna |  | 0.125 | 6.533 | 2.711 | 0.817 | 1.95 | 0.339 | 0.244 | 3.35 | NEMSOK - Object Layer Attributes #1, Kód prvku: SN07.03.0001; Object Layer Attributes #1, Podlaží: 1.NP; Object Layer Attributes #1, Požární odolnost: EI 60; Object Layer Attributes #1, Funkce (venkovní): Ne; Object Layer Attributes #1, Statická funkce: Ne; Object Layer Attributes #1, Vážená stavební neprůzvučnost: 54; Object Layer Attributes #1, Vlhkostní namáhání oboustranné: Ne; Object Layer Attributes #1, Tloušťka opláštění: 2×12,5; Object Layer Attributes #1, Typ SDK desky: vysokopevnostní+bílá; Object Layer Attributes #1, Způsob opláštění: Oboustranné; Object Layer Attributes #1, Tloušťka izolace (2): 75; Object Layer Attributes #1, Objemová hmotnost izolace: 25; Object Layer Attributes #1, Typ profilu pro SDK: CW 75; Object Layer Attributes #1, Rozteč rastru: 625
SDK INSTAL. PŘDSTĚNA VYSOKÁ | Půdorys 1.NP | SDK INSTAL. PŘDSTĚNA VYSOKÁ 0.2 m |  | SDK INSTAL. PŘDSTĚNA VYSOKÁ |  | 1464HWa1096312799 | m3 | Celá stěna | Nový | Suché stavební práce | SDK INSTAL. PŘDSTĚNA VYSOKÁ | no | 1464Stě1096312801 | m3 | Stěna |  | 0.2 | 2.925 | 2.925 | 0.585 | 0.9 | 0.585 | 0.18 | 3.25 | NEMSOK - Object Layer Attributes #1, Kód prvku: SN07.03.0001; Object Layer Attributes #1, Podlaží: 1.NP; Object Layer Attributes #1, Požární odolnost: bez požadavku; Object Layer Attributes #1, Funkce (venkovní): Ne; Object Layer Attributes #1, Statická funkce: Ne; Object Layer Attributes #1, Vlhkostní namáhání oboustranné: Ne; Object Layer Attributes #1, Tloušťka opláštění: 2×12,5; Object Layer Attributes #1, Typ SDK desky: impregnovaná; Object Layer Attributes #1, Způsob opláštění: Jednostranné; Object Layer Attributes #1, Tloušťka izolace (2): 0; Object Layer Attributes #1, Objemová hmotnost izolace: 0; Object Layer Attributes #1, Typ profilu pro SDK: CW 100; Object Layer Attributes #1, Rozteč rastru: 625
SDK OPL. PROFESÍ/SDK OPL. BEZ PO | Půdorys 1.NP | SDK OPL. PROFESÍ/SDK OPL. BEZ PO 0.1 m |  | SDK OPL. PROFESÍ/SDK OPL. BEZ PO |  | 1464HWa1096312803 | m3 | Celá stěna | Nový | Suché stavební práce | SDK OPL. PROFESÍ/SDK OPL. BEZ PO | no | 1464Stě1096314285 | m3 | Stěna |  | 0.1 | 7.475 | 7.37 | 0.747 | 2.3 | 0.737 | 0.23 | 3.25 | NEMSOK - Object Layer Attributes #1, Kód prvku: SN07.03.0001; Object Layer Attributes #1, Podlaží: 1.NP; Object Layer Attributes #1, Požární odolnost: bez požadavku; Object Layer Attributes #1, Funkce (venkovní): Ne; Object Layer Attributes #1, Statická funkce: Ne; Object Layer Attributes #1, Vlhkostní namáhání oboustranné: Ne; Object Layer Attributes #1, Tloušťka opláštění: 2×12,5; Object Layer Attributes #1, Typ SDK desky: vysokopevnostní+bílá; Object Layer Attributes #1, Způsob opláštění: Jednostranné; Object Layer Attributes #1, Tloušťka izolace (2): 0; Object Layer Attributes #1, Objemová hmotnost izolace: 0; Object Layer Attributes #1, Typ profilu pro SDK: CW 75; Object Layer Attributes #1, Rozteč rastru: 625
SDK - 1 KCE + DVOJITÉ OPLÁŠTĚNÍ | Půdorys 1.NP | SDK - 1 KCE + DVOJITÉ OPLÁŠTĚNÍ 0.15 m |  | SDK - 1 KCE + DVOJITÉ OPLÁŠTĚNÍ |  | 1464HWa1096312805 | m3 | Celá stěna | Nový | Suché stavební práce | SDK - 1 KCE + DVOJITÉ OPLÁŠTĚNÍ | no | 1464Stě1096313588 | m3 | Stěna |  | 0.15 | 16.465 | 16.324 | 2.47 | 4.45 | 2.449 | 0.668 | 3.7 | NEMSOK - Object Layer Attributes #1, Kód prvku: SN07.03.0001; Object Layer Attributes #1, Podlaží: 1.NP; Object Layer Attributes #1, Požární odolnost: EI 60; Object Layer Attributes #1, Funkce (venkovní): Ne; Object Layer Attributes #1, Statická funkce: Ne; Object Layer Attributes #1, Vážená stavební neprůzvučnost: 54; Object Layer Attributes #1, Vlhkostní namáhání oboustranné: Ne; Object Layer Attributes #1, Tloušťka opláštění: 2×12,5; Object Layer Attributes #1, Typ SDK desky: vysokopevnostní+bílá; Object Layer Attributes #1, Způsob opláštění: Oboustranné; Object Layer Attributes #1, Tloušťka izolace (2): 100; Object Layer Attributes #1, Objemová hmotnost izolace: 25; Object Layer Attributes #1, Typ profilu pro SDK: CW 100; Object Layer Attributes #1, Rozteč rastru: 625
SDK OPL. PROFESÍ/SDK OPL. BEZ PO | Půdorys 1.NP | SDK OPL. PROFESÍ/SDK OPL. BEZ PO 0.1 m |  | SDK OPL. PROFESÍ/SDK OPL. BEZ PO |  | 1464HWa1096312808 | m3 | Celá stěna | Nový | Suché stavební práce | SDK OPL. PROFESÍ/SDK OPL. BEZ PO | no | 1464Stě1096312817 | m3 | Stěna |  | 0.1 | 9.065 | 9.065 | 0.906 | 2.45 | 0.906 | 0.245 | 3.7 | NEMSOK - Object Layer Attributes #1, Kód prvku: SN07.03.0001; Object Layer Attributes #1, Podlaží: 1.NP; Object Layer Attributes #1, Požární odolnost: bez požadavku; Object Layer Attributes #1, Funkce (venkovní): Ne; Object Layer Attributes #1, Statická funkce: Ne; Object Layer Attributes #1, Vlhkostní namáhání oboustranné: Ne; Object Layer Attributes #1, Tloušťka opláštění: 2×12,5; Object Layer Attributes #1, Typ SDK desky: vysokopevnostní+bílá; Object Layer Attributes #1, Způsob opláštění: Jednostranné; Object Layer Attributes #1, Tloušťka izolace (2): 0; Object Layer Attributes #1, Objemová hmotnost izolace: 0; Object Layer Attributes #1, Typ profilu pro SDK: CW 75; Object Layer Attributes #1, Rozteč rastru: 625
SDK OPL. PROFESÍ/SDK OPL. BEZ PO | Půdorys 1.NP | SDK OPL. PROFESÍ/SDK OPL. BEZ PO 0.1 m |  | SDK OPL. PROFESÍ/SDK OPL. BEZ PO |  | 1464HWa1096312809 | m3 | Celá stěna | Nový | Suché stavební práce | SDK OPL. PROFESÍ/SDK OPL. BEZ PO | no | 1464Stě1096312815 | m3 | Stěna |  | 0.1 | 5.162 | 5.162 | 0.516 | 1.395 | 0.516 | 0.14 | 3.7 | NEMSOK - Object Layer Attributes #1, Kód prvku: SN07.03.0001; Object Layer Attributes #1, Podlaží: 1.NP; Object Layer Attributes #1, Požární odolnost: bez požadavku; Object Layer Attributes #1, Funkce (venkovní): Ne; Object Layer Attributes #1, Statická funkce: Ne; Object Layer Attributes #1, Vlhkostní namáhání oboustranné: Ne; Object Layer Attributes #1, Tloušťka opláštění: 2×12,5; Object Layer Attributes #1, Typ SDK desky: vysokopevnostní+bílá; Object Layer Attributes #1, Způsob opláštění: Jednostranné; Object Layer Attributes #1, Tloušťka izolace (2): 0; Object Layer Attributes #1, Objemová hmotnost izolace: 0; Object Layer Attributes #1, Typ profilu pro SDK: CW 75; Object Layer Attributes #1, Rozteč rastru: 625
SDK - 1 KCE + DVOJITÉ OPLÁŠTĚNÍ | Půdorys 1.NP | SDK - 1 KCE + DVOJITÉ OPLÁŠTĚNÍ 0.125 m |  | SDK - 1 KCE + DVOJITÉ OPLÁŠTĚNÍ |  | 1464HWa1096312812 | m3 | Celá stěna | Nový | Suché stavební práce | SDK - 1 KCE + DVOJITÉ OPLÁŠTĚNÍ | no | 1464Stě1096313000 | m3 | Stěna |  | 0.125 | 10.249 | 8.044 | 1.281 | 2.77 | 1.006 | 0.346 | 3.7 | NEMSOK - Object Layer Attributes #1, Kód prvku: SN07.03.0001; Object Layer Attributes #1, Podlaží: 1.NP; Object Layer Attributes #1, Požární odolnost: EI 60; Object Layer Attributes #1, Funkce (venkovní): Ne; Object Layer Attributes #1, Statická funkce: Ne; Object Layer Attributes #1, Vážená stavební neprůzvučnost: 54; Object Layer Attributes #1, Vlhkostní namáhání oboustranné: Ne; Object Layer Attributes #1, Tloušťka opláštění: 2×12,5; Object Layer Attributes #1, Typ SDK desky: vysokopevnostní+bílá; Object Layer Attributes #1, Způsob opláštění: Oboustranné; Object Layer Attributes #1, Tloušťka izolace (2): 75; Object Layer Attributes #1, Objemová hmotnost izolace: 25; Object Layer Attributes #1, Typ profilu pro SDK: CW 75; Object Layer Attributes #1, Rozteč rastru: 625
SDK OPL. PROFESÍ/SDK OPL. BEZ PO | Půdorys 1.NP | SDK OPL. PROFESÍ/SDK OPL. BEZ PO 0.075 m |  | SDK OPL. PROFESÍ/SDK OPL. BEZ PO |  | 1464HWa1096312818 | m3 | Celá stěna | Nový | Suché stavební práce | SDK OPL. PROFESÍ/SDK OPL. BEZ PO | no | 1464Stě1096313247 | m3 | Stěna |  | 0.075 | 0.325 | 0.325 | 0.024 | 0.1 | 0.024 | 0.008 | 3.25 | NEMSOK - Object Layer Attributes #1, Kód prvku: SN07.03.0001; Object Layer Attributes #1, Podlaží: 1.NP; Object Layer Attributes #1, Požární odolnost: bez požadavku; Object Layer Attributes #1, Funkce (venkovní): Ne; Object Layer Attributes #1, Statická funkce: Ne; Object Layer Attributes #1, Vlhkostní namáhání oboustranné: Ne; Object Layer Attributes #1, Tloušťka opláštění: 2×12,5; Object Layer Attributes #1, Typ SDK desky: vysokopevnostní+bílá; Object Layer Attributes #1, Způsob opláštění: Jednostranné; Object Layer Attributes #1, Tloušťka izolace (2): 0; Object Layer Attributes #1, Objemová hmotnost izolace: 0; Object Layer Attributes #1, Typ profilu pro SDK: CW 100; Object Layer Attributes #1, Rozteč rastru: 625
SDK OPL. PROFESÍ/SDK OPL. BEZ PO | Půdorys 1.NP | SDK OPL. PROFESÍ/SDK OPL. BEZ PO 0.075 m |  | SDK OPL. PROFESÍ/SDK OPL. BEZ PO |  | 1464HWa1096312820 | m3 | Celá stěna | Nový | Suché stavební práce | SDK OPL. PROFESÍ/SDK OPL. BEZ PO | no | 1464Stě1096313245 | m3 | Stěna |  | 0.075 | 0.325 | 0.325 | 0.024 | 0.1 | 0.024 | 0.007 | 3.25 | NEMSOK - Object Layer Attributes #1, Kód prvku: SN07.03.0001; Object Layer Attributes #1, Podlaží: 1.NP; Object Layer Attributes #1, Požární odolnost: bez požadavku; Object Layer Attributes #1, Funkce (venkovní): Ne; Object Layer Attributes #1, Statická funkce: Ne; Object Layer Attributes #1, Vlhkostní namáhání oboustranné: Ne; Object Layer Attributes #1, Tloušťka opláštění: 2×12,5; Object Layer Attributes #1, Typ SDK desky: vysokopevnostní+bílá; Object Layer Attributes #1, Způsob opláštění: Jednostranné; Object Layer Attributes #1, Tloušťka izolace (2): 0; Object Layer Attributes #1, Objemová hmotnost izolace: 0; Object Layer Attributes #1, Typ profilu pro SDK: CW 100; Object Layer Attributes #1, Rozteč rastru: 625
SDK OPL. PROFESÍ/SDK OPL. BEZ PO | Půdorys 1.NP | SDK OPL. PROFESÍ/SDK OPL. BEZ PO 0.075 m |  | SDK OPL. PROFESÍ/SDK OPL. BEZ PO |  | 1464HWa1096312822 | m3 | Celá stěna | Nový | Suché stavební práce | SDK OPL. PROFESÍ/SDK OPL. BEZ PO | no | 1464Stě1096313237 | m3 | Stěna |  | 0.075 | 1.462 | 1.463 | 0.11 | 0.45 | 0.11 | 0.034 | 3.25 | NEMSOK - Object Layer Attributes #1, Kód prvku: SN07.03.0001; Object Layer Attributes #1, Podlaží: 1.NP; Object Layer Attributes #1, Požární odolnost: bez požadavku; Object Layer Attributes #1, Funkce (venkovní): Ne; Object Layer Attributes #1, Statická funkce: Ne; Object Layer Attributes #1, Vlhkostní namáhání oboustranné: Ne; Object Layer Attributes #1, Tloušťka opláštění: 2×12,5; Object Layer Attributes #1, Typ SDK desky: vysokopevnostní+bílá; Object Layer Attributes #1, Způsob opláštění: Jednostranné; Object Layer Attributes #1, Tloušťka izolace (2): 0; Object Layer Attributes #1, Objemová hmotnost izolace: 0; Object Layer Attributes #1, Typ profilu pro SDK: CW 100; Object Layer Attributes #1, Rozteč rastru: 625
SDK - 1 KCE + DVOJITÉ OPLÁŠTĚNÍ | Půdorys 1.NP | SDK - 1 KCE + DVOJITÉ OPLÁŠTĚNÍ 0.2 m |  | SDK - 1 KCE + DVOJITÉ OPLÁŠTĚNÍ |  | 1464HWa1096312824 | m3 | Celá stěna | Nový | Suché stavební práce | SDK - 1 KCE + DVOJITÉ OPLÁŠTĚNÍ | no | 1464Stě1096313873 | m3 | Stěna |  | 0.2 | 18.09 | 17.94 | 3.618 | 5.4 | 3.588 | 1.08 | 3.35 | NEMSOK - Object Layer Attributes #1, Kód prvku: SN07.03.0001; Object Layer Attributes #1, Podlaží: 1.NP; Object Layer Attributes #1, Požární odolnost: EI 60; Object Layer Attributes #1, Funkce (venkovní): Ne; Object Layer Attributes #1, Statická funkce: Ne; Object Layer Attributes #1, Vážená stavební neprůzvučnost: 54; Object Layer Attributes #1, Vlhkostní namáhání oboustranné: Ne; Object Layer Attributes #1, Tloušťka opláštění: 2×12,5; Object Layer Attributes #1, Typ SDK desky: vysokopevnostní+bílá; Object Layer Attributes #1, Způsob opláštění: Oboustranné; Object Layer Attributes #1, Tloušťka izolace (2): 150; Object Layer Attributes #1, Objemová hmotnost izolace: 25; Object Layer Attributes #1, Typ profilu pro SDK: CW 150; Object Layer Attributes #1, Rozteč rastru: 625
SDK ŠACHTOVÁ STĚNA/SDK OPL. S PO | Půdorys 1.NP | SDK ŠACHTOVÁ STĚNA/SDK OPL. S PO 0.1 m |  | SDK ŠACHTOVÁ STĚNA/SDK OPL. S PO |  | 1464HWa1096312826 | m3 | Celá stěna | Nový | Suché stavební práce | SDK ŠACHTOVÁ STĚNA/SDK OPL. S PO | no | 1464Stě1096313487 | m3 | Stěna |  | 0.1 | 3.575 | 2.855 | 0.358 | 1.1 | 0.286 | 0.11 | 3.25 | NEMSOK - Object Layer Attributes #1, Kód prvku: SN07.03.0001; Object Layer Attributes #1, Podlaží: 1.NP; Object Layer Attributes #1, Požární odolnost: bez požadavku; Object Layer Attributes #1, Funkce (venkovní): Ne; Object Layer Attributes #1, Statická funkce: Ne; Object Layer Attributes #1, Vlhkostní namáhání oboustranné: Ne; Object Layer Attributes #1, Tloušťka opláštění: 2×12,5; Object Layer Attributes #1, Typ SDK desky: vysokopevnostní+bílá; Object Layer Attributes #1, Způsob opláštění: Jednostranné; Object Layer Attributes #1, Tloušťka izolace (2): 0; Object Layer Attributes #1, Objemová hmotnost izolace: 0; Object Layer Attributes #1, Typ profilu pro SDK: CW 75; Object Layer Attributes #1, Rozteč rastru: 625
SDK ŠACHTOVÁ STĚNA/SDK OPL. S PO | Půdorys 1.NP | SDK ŠACHTOVÁ STĚNA/SDK OPL. S PO 0.1 m |  | SDK ŠACHTOVÁ STĚNA/SDK OPL. S PO |  | 1464HWa1096312828 | m3 | Celá stěna | Nový | Suché stavební práce | SDK ŠACHTOVÁ STĚNA/SDK OPL. S PO | no | 1464Stě1096312843 | m3 | Stěna |  | 0.1 | 1.95 | 1.95 | 0.195 | 0.6 | 0.195 | 0.06 | 3.25 | NEMSOK - Object Layer Attributes #1, Kód prvku: SN07.03.0001; Object Layer Attributes #1, Podlaží: 1.NP; Object Layer Attributes #1, Požární odolnost: bez požadavku; Object Layer Attributes #1, Funkce (venkovní): Ne; Object Layer Attributes #1, Statická funkce: Ne; Object Layer Attributes #1, Vlhkostní namáhání oboustranné: Ne; Object Layer Attributes #1, Tloušťka opláštění: 2×12,5; Object Layer Attributes #1, Typ SDK desky: vysokopevnostní+bílá; Object Layer Attributes #1, Způsob opláštění: Jednostranné; Object Layer Attributes #1, Tloušťka izolace (2): 0; Object Layer Attributes #1, Objemová hmotnost izolace: 0; Object Layer Attributes #1, Typ profilu pro SDK: CW 75; Object Layer Attributes #1, Rozteč rastru: 625
SDK ŠACHTOVÁ STĚNA/SDK OPL. S PO | Půdorys 1.NP | SDK ŠACHTOVÁ STĚNA/SDK OPL. S PO 0.1 m |  | SDK ŠACHTOVÁ STĚNA/SDK OPL. S PO |  | 1464HWa1096312830 | m3 | Celá stěna | Nový | Suché stavební práce | SDK ŠACHTOVÁ STĚNA/SDK OPL. S PO | no | 1464Stě1096312915 | m3 | Stěna |  | 0.1 | 2.031 | 2.031 | 0.203 | 0.625 | 0.203 | 0.063 | 3.25 | NEMSOK - Object Layer Attributes #1, Kód prvku: SN07.03.0001; Object Layer Attributes #1, Podlaží: 1.NP; Object Layer Attributes #1, Požární odolnost: bez požadavku; Object Layer Attributes #1, Funkce (venkovní): Ne; Object Layer Attributes #1, Statická funkce: Ne; Object Layer Attributes #1, Vlhkostní namáhání oboustranné: Ne; Object Layer Attributes #1, Tloušťka opláštění: 2×12,5; Object Layer Attributes #1, Typ SDK desky: vysokopevnostní+bílá; Object Layer Attributes #1, Způsob opláštění: Jednostranné; Object Layer Attributes #1, Tloušťka izolace (2): 0; Object Layer Attributes #1, Objemová hmotnost izolace: 0; Object Layer Attributes #1, Typ profilu pro SDK: CW 75; Object Layer Attributes #1, Rozteč rastru: 625
SDK ŠACHTOVÁ STĚNA/SDK OPL. S PO | Půdorys 1.NP | SDK ŠACHTOVÁ STĚNA/SDK OPL. S PO 0.1 m |  | SDK ŠACHTOVÁ STĚNA/SDK OPL. S PO |  | 1464HWa1096312831 | m3 | Celá stěna | Nový | Suché stavební práce | SDK ŠACHTOVÁ STĚNA/SDK OPL. S PO | no | 1464Stě1096312856 | m3 | Stěna |  | 0.1 | 3.25 | 3.25 | 0.325 | 1 | 0.325 | 0.1 | 3.25 | NEMSOK - Object Layer Attributes #1, Kód prvku: SN07.03.0001; Object Layer Attributes #1, Podlaží: 1.NP; Object Layer Attributes #1, Požární odolnost: bez požadavku; Object Layer Attributes #1, Funkce (venkovní): Ne; Object Layer Attributes #1, Statická funkce: Ne; Object Layer Attributes #1, Vlhkostní namáhání oboustranné: Ne; Object Layer Attributes #1, Tloušťka opláštění: 2×12,5; Object Layer Attributes #1, Typ SDK desky: vysokopevnostní+bílá; Object Layer Attributes #1, Způsob opláštění: Jednostranné; Object Layer Attributes #1, Tloušťka izolace (2): 0; Object Layer Attributes #1, Objemová hmotnost izolace: 0; Object Layer Attributes #1, Typ profilu pro SDK: CW 75; Object Layer Attributes #1, Rozteč rastru: 625
SDK ŠACHTOVÁ STĚNA/SDK OPL. S PO | Půdorys 1.NP | SDK ŠACHTOVÁ STĚNA/SDK OPL. S PO 0.1 m |  | SDK ŠACHTOVÁ STĚNA/SDK OPL. S PO |  | 1464HWa1096312833 | m3 | Celá stěna | Nový | Suché stavební práce | SDK ŠACHTOVÁ STĚNA/SDK OPL. S PO | no | 1464Stě1096313431 | m3 | Stěna |  | 0.1 | 5.2 | 5.2 | 0.52 | 1.6 | 0.52 | 0.16 | 3.25 | NEMSOK - Object Layer Attributes #1, Kód prvku: SN07.03.0001; Object Layer Attributes #1, Podlaží: 1.NP; Object Layer Attributes #1, Požární odolnost: bez požadavku; Object Layer Attributes #1, Funkce (venkovní): Ne; Object Layer Attributes #1, Statická funkce: Ne; Object Layer Attributes #1, Vlhkostní namáhání oboustranné: Ne; Object Layer Attributes #1, Tloušťka opláštění: 2×12,5; Object Layer Attributes #1, Typ SDK desky: vysokopevnostní+bílá; Object Layer Attributes #1, Způsob opláštění: Jednostranné; Object Layer Attributes #1, Tloušťka izolace (2): 0; Object Layer Attributes #1, Objemová hmotnost izolace: 0; Object Layer Attributes #1, Typ profilu pro SDK: CW 75; Object Layer Attributes #1, Rozteč rastru: 625
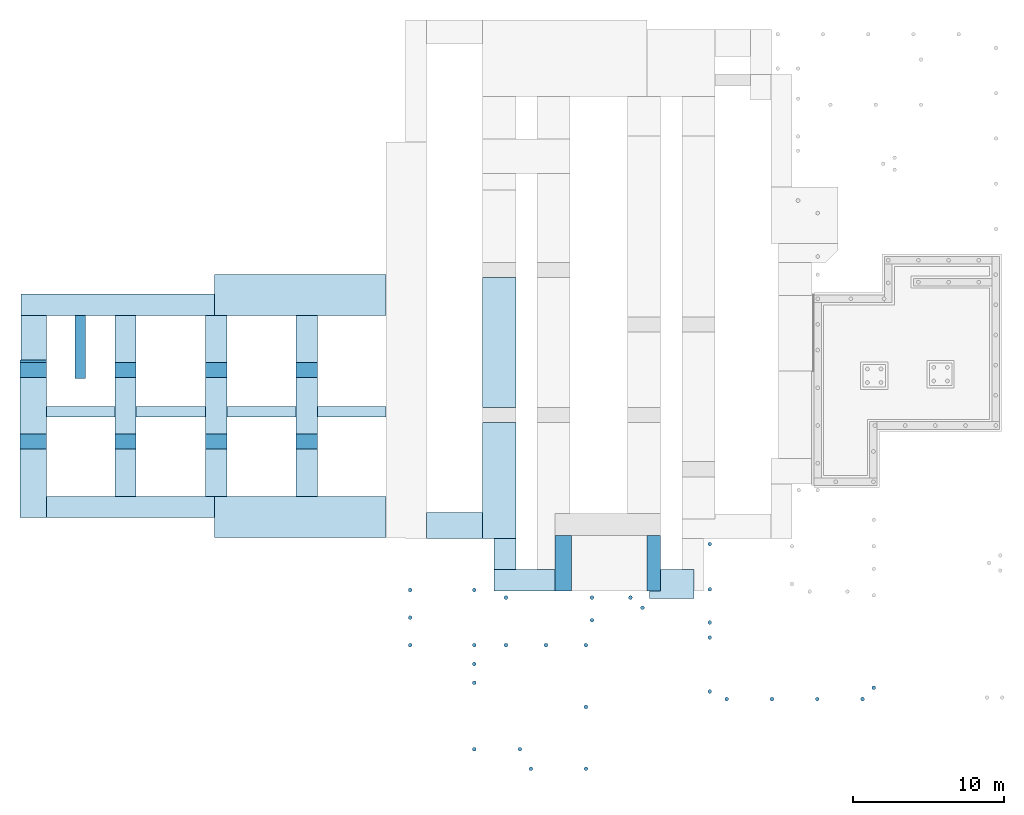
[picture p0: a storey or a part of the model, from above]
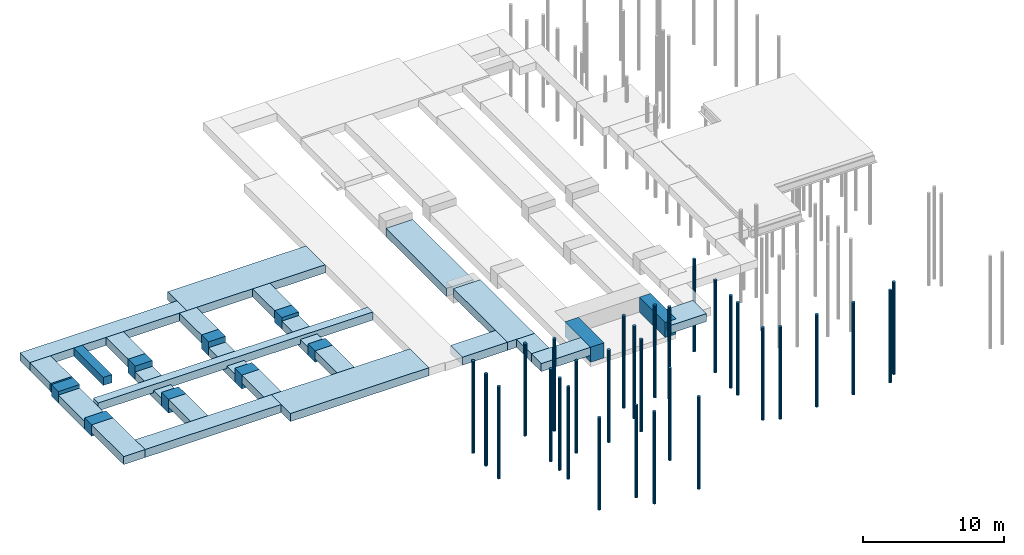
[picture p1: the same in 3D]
Properties of the parts of a building model (IFC4), part 35 of 45

# IfcWall (2385)
Name | In | Material | Faktor | Označení | Požární odolnost | Allright_Stavebni_dil_ID | Jednotka | Název_objektu | Object Layer Attributes #1, Status | Object Layer Attributes #1, Práce | Object Layer Attributes #1, Materiál | Object Layer Attributes #1, Staticky nosná konstrukce | Object Layer Attributes #1, Allright_Stavebni_dil_ID | Object Layer Attributes #1, Jednotka | Object Layer Attributes #1, Název_objektu | ThermalTransmittance (W/K/m2) | Width (m) | GrossSideArea (m2) | NetSideArea (m2) | GrossVolume (m3) | Length (m) | NetVolume (m3) | GrossFootprintArea (m2) | Height (m)
SDK - 2 KCE + DVOJITÉ OPLÁŠTĚNÍ | Půdorys 1.NP | SDK - 2 KCE + DVOJITÉ OPLÁŠTĚNÍ 0.25 m |  | SDK - 2 KCE + DVOJITÉ OPLÁŠTĚNÍ |  | 1464HWa1096312835 | m3 | Celá stěna | Nový | Suché stavební práce | SDK - 2 KCE + DVOJITÉ OPLÁŠTĚNÍ | no | 1464Stě1096314568 | m3 | Stěna |  | 0.25 | 19.262 | 15.412 | 4.816 | 5.206 | 3.844 | 1.301 | 3.7 | NEMSOK - Object Layer Attributes #1, Kód prvku: SN07.03.0001; Object Layer Attributes #1, Podlaží: 1.NP; Object Layer Attributes #1, Požární odolnost: EI 60; Object Layer Attributes #1, Funkce (venkovní): Ne; Object Layer Attributes #1, Statická funkce: Ne; Object Layer Attributes #1, Vážená stavební neprůzvučnost: 54; Object Layer Attributes #1, Vlhkostní namáhání oboustranné: Ne; Object Layer Attributes #1, Tloušťka opláštění: 2×12,5; Object Layer Attributes #1, Typ SDK desky: vysokopevnostní+bílá; Object Layer Attributes #1, Způsob opláštění: Oboustranné; Object Layer Attributes #1, Tloušťka izolace (2): 100; Object Layer Attributes #1, Objemová hmotnost izolace: 25; Object Layer Attributes #1, Typ profilu pro SDK: 2× CW 100; Object Layer Attributes #1, Rozteč rastru: 625
SDK OPL. PROFESÍ/SDK OPL. BEZ PO | Půdorys 1.NP | SDK OPL. PROFESÍ/SDK OPL. BEZ PO 0.1 m |  | SDK OPL. PROFESÍ/SDK OPL. BEZ PO |  | 1464HWa1096312840 | m3 | Celá stěna | Nový | Suché stavební práce | SDK OPL. PROFESÍ/SDK OPL. BEZ PO | no | 1464Stě1096314245 | m3 | Stěna |  | 0.1 | 2.925 | 2.925 | 0.293 | 0.9 | 0.293 | 0.09 | 3.25 | NEMSOK - Object Layer Attributes #1, Kód prvku: SN07.03.0001; Object Layer Attributes #1, Podlaží: 1.NP; Object Layer Attributes #1, Požární odolnost: bez požadavku; Object Layer Attributes #1, Funkce (venkovní): Ne; Object Layer Attributes #1, Statická funkce: Ne; Object Layer Attributes #1, Vlhkostní namáhání oboustranné: Ne; Object Layer Attributes #1, Tloušťka opláštění: 2×12,5; Object Layer Attributes #1, Typ SDK desky: vysokopevnostní+bílá; Object Layer Attributes #1, Způsob opláštění: Jednostranné; Object Layer Attributes #1, Tloušťka izolace (2): 0; Object Layer Attributes #1, Objemová hmotnost izolace: 0; Object Layer Attributes #1, Typ profilu pro SDK: CW 75; Object Layer Attributes #1, Rozteč rastru: 625
SDK - 1 KCE + DVOJITÉ OPLÁŠTĚNÍ | Půdorys 1.NP | SDK - 1 KCE + DVOJITÉ OPLÁŠTĚNÍ 0.15 m |  | SDK - 1 KCE + DVOJITÉ OPLÁŠTĚNÍ |  | 1464HWa1096312846 | m3 | Celá stěna | Nový | Suché stavební práce | SDK - 1 KCE + DVOJITÉ OPLÁŠTĚNÍ | no | 1464Stě1096314200 | m3 | Stěna |  | 0.15 | 11.055 | 10.89 | 1.658 | 3.3 | 1.633 | 0.495 | 3.35 | NEMSOK - Object Layer Attributes #1, Kód prvku: SN07.03.0001; Object Layer Attributes #1, Podlaží: 1.NP; Object Layer Attributes #1, Požární odolnost: EI 60; Object Layer Attributes #1, Funkce (venkovní): Ne; Object Layer Attributes #1, Statická funkce: Ne; Object Layer Attributes #1, Vážená stavební neprůzvučnost: 54; Object Layer Attributes #1, Vlhkostní namáhání oboustranné: Ne; Object Layer Attributes #1, Tloušťka opláštění: 2×12,5; Object Layer Attributes #1, Typ SDK desky: vysokopevnostní+bílá; Object Layer Attributes #1, Způsob opláštění: Oboustranné; Object Layer Attributes #1, Tloušťka izolace (2): 100; Object Layer Attributes #1, Objemová hmotnost izolace: 25; Object Layer Attributes #1, Typ profilu pro SDK: CW 100; Object Layer Attributes #1, Rozteč rastru: 625
SDK - 2 KCE + DVOJITÉ OPLÁŠTĚNÍ | Půdorys 1.NP | SDK - 2 KCE + DVOJITÉ OPLÁŠTĚNÍ 0.25 m |  | SDK - 2 KCE + DVOJITÉ OPLÁŠTĚNÍ |  | 1464HWa1096312848 | m3 | Celá stěna | Nový | Suché stavební práce | SDK - 2 KCE + DVOJITÉ OPLÁŠTĚNÍ | no | 1464Stě1096312913 | m3 | Stěna |  | 0.25 | 3.015 | 3.015 | 0.754 | 0.9 | 0.754 | 0.225 | 3.35 | NEMSOK - Object Layer Attributes #1, Kód prvku: SN07.03.0001; Object Layer Attributes #1, Podlaží: 1.NP; Object Layer Attributes #1, Požární odolnost: EI 60; Object Layer Attributes #1, Funkce (venkovní): Ne; Object Layer Attributes #1, Statická funkce: Ne; Object Layer Attributes #1, Vážená stavební neprůzvučnost: 54; Object Layer Attributes #1, Vlhkostní namáhání oboustranné: Ne; Object Layer Attributes #1, Tloušťka opláštění: 2×12,5; Object Layer Attributes #1, Typ SDK desky: vysokopevnostní+bílá; Object Layer Attributes #1, Způsob opláštění: Oboustranné; Object Layer Attributes #1, Tloušťka izolace (2): 100; Object Layer Attributes #1, Objemová hmotnost izolace: 25; Object Layer Attributes #1, Typ profilu pro SDK: 2× CW 100; Object Layer Attributes #1, Rozteč rastru: 625
SDK - 2 KCE + DVOJITÉ OPLÁŠTĚNÍ | Půdorys 1.NP | SDK - 2 KCE + DVOJITÉ OPLÁŠTĚNÍ 0.25 m |  | SDK - 2 KCE + DVOJITÉ OPLÁŠTĚNÍ |  | 1464HWa1096312850 | m3 | Celá stěna | Nový | Suché stavební práce | SDK - 2 KCE + DVOJITÉ OPLÁŠTĚNÍ | no | 1464Stě1096313483 | m3 | Stěna |  | 0.25 | 3.936 | 3.513 | 0.984 | 1.175 | 0.91 | 0.294 | 3.35 | NEMSOK - Object Layer Attributes #1, Kód prvku: SN07.03.0001; Object Layer Attributes #1, Podlaží: 1.NP; Object Layer Attributes #1, Požární odolnost: EI 60; Object Layer Attributes #1, Funkce (venkovní): Ne; Object Layer Attributes #1, Statická funkce: Ne; Object Layer Attributes #1, Vážená stavební neprůzvučnost: 54; Object Layer Attributes #1, Vlhkostní namáhání oboustranné: Ne; Object Layer Attributes #1, Tloušťka opláštění: 2×12,5; Object Layer Attributes #1, Typ SDK desky: vysokopevnostní+bílá; Object Layer Attributes #1, Způsob opláštění: Oboustranné; Object Layer Attributes #1, Tloušťka izolace (2): 100; Object Layer Attributes #1, Objemová hmotnost izolace: 25; Object Layer Attributes #1, Typ profilu pro SDK: 2× CW 100; Object Layer Attributes #1, Rozteč rastru: 625
SDK - 1 KCE + DVOJITÉ OPLÁŠTĚNÍ | Půdorys 1.NP | SDK - 1 KCE + DVOJITÉ OPLÁŠTĚNÍ 0.15 m |  | SDK - 1 KCE + DVOJITÉ OPLÁŠTĚNÍ |  | 1464HWa1096312853 | m3 | Celá stěna | Nový | Suché stavební práce | SDK - 1 KCE + DVOJITÉ OPLÁŠTĚNÍ | no | 1464Stě1096314236 | m3 | Stěna |  | 0.15 | 18.09 | 17.872 | 2.713 | 5.4 | 2.681 | 0.81 | 3.35 | NEMSOK - Object Layer Attributes #1, Kód prvku: SN07.03.0001; Object Layer Attributes #1, Podlaží: 1.NP; Object Layer Attributes #1, Požární odolnost: EI 60; Object Layer Attributes #1, Funkce (venkovní): Ne; Object Layer Attributes #1, Statická funkce: Ne; Object Layer Attributes #1, Vážená stavební neprůzvučnost: 54; Object Layer Attributes #1, Vlhkostní namáhání oboustranné: Ne; Object Layer Attributes #1, Tloušťka opláštění: 2×12,5; Object Layer Attributes #1, Typ SDK desky: vysokopevnostní+bílá; Object Layer Attributes #1, Způsob opláštění: Oboustranné; Object Layer Attributes #1, Tloušťka izolace (2): 100; Object Layer Attributes #1, Objemová hmotnost izolace: 25; Object Layer Attributes #1, Typ profilu pro SDK: CW 100; Object Layer Attributes #1, Rozteč rastru: 625
SDK INSTAL. PŘDSTĚNA VYSOKÁ | Půdorys 1.NP | SDK INSTAL. PŘDSTĚNA VYSOKÁ 0.149988 m |  | SDK INSTAL. PŘDSTĚNA VYSOKÁ |  | 1464HWa1096312859 | m3 | Celá stěna | Nový | Suché stavební práce | SDK INSTAL. PŘDSTĚNA VYSOKÁ | no | 1464Stě1096312874 | m3 | Stěna |  | 0.15 | 9.18 | 9.18 | 1.377 | 2.7 | 1.377 | 0.405 | 3.4 | NEMSOK - Object Layer Attributes #1, Kód prvku: SN07.03.0001; Object Layer Attributes #1, Podlaží: 1.NP; Object Layer Attributes #1, Požární odolnost: bez požadavku; Object Layer Attributes #1, Funkce (venkovní): Ne; Object Layer Attributes #1, Statická funkce: Ne; Object Layer Attributes #1, Vlhkostní namáhání oboustranné: Ne; Object Layer Attributes #1, Tloušťka opláštění: 2×12,5; Object Layer Attributes #1, Typ SDK desky: impregnovaná; Object Layer Attributes #1, Způsob opláštění: Jednostranné; Object Layer Attributes #1, Tloušťka izolace (2): 0; Object Layer Attributes #1, Objemová hmotnost izolace: 0; Object Layer Attributes #1, Typ profilu pro SDK: CW 100; Object Layer Attributes #1, Rozteč rastru: 625
SDK - 1 KCE + DVOJITÉ OPLÁŠTĚNÍ | Půdorys 1.NP | SDK - 1 KCE + DVOJITÉ OPLÁŠTĚNÍ 0.15 m |  | SDK - 1 KCE + DVOJITÉ OPLÁŠTĚNÍ |  | 1464HWa1096312860 | m3 | Celá stěna | Nový | Suché stavební práce | SDK - 1 KCE + DVOJITÉ OPLÁŠTĚNÍ | no | 1464Stě1096314719 | m3 | Stěna |  | 0.15 | 4.439 | 4.295 | 0.666 | 1.325 | 0.644 | 0.199 | 3.35 | NEMSOK - Object Layer Attributes #1, Kód prvku: SN07.03.0001; Object Layer Attributes #1, Podlaží: 1.NP; Object Layer Attributes #1, Požární odolnost: EI 60; Object Layer Attributes #1, Funkce (venkovní): Ne; Object Layer Attributes #1, Statická funkce: Ne; Object Layer Attributes #1, Vážená stavební neprůzvučnost: 54; Object Layer Attributes #1, Vlhkostní namáhání oboustranné: Ne; Object Layer Attributes #1, Tloušťka opláštění: 2×12,5; Object Layer Attributes #1, Typ SDK desky: vysokopevnostní+bílá; Object Layer Attributes #1, Způsob opláštění: Oboustranné; Object Layer Attributes #1, Tloušťka izolace (2): 100; Object Layer Attributes #1, Objemová hmotnost izolace: 25; Object Layer Attributes #1, Typ profilu pro SDK: CW 100; Object Layer Attributes #1, Rozteč rastru: 625
SDK OPL. PROFESÍ/SDK OPL. BEZ PO | Půdorys 1.NP | SDK OPL. PROFESÍ/SDK OPL. BEZ PO 0.075 m |  | SDK OPL. PROFESÍ/SDK OPL. BEZ PO |  | 1464HWa1096312864 | m3 | Celá stěna | Nový | Suché stavební práce | SDK OPL. PROFESÍ/SDK OPL. BEZ PO | no | 1464Stě1096314247 | m3 | Stěna |  | 0.075 | 0.976 | 0.976 | 0.073 | 0.275 | 0.073 | 0.021 | 3.55 | NEMSOK - Object Layer Attributes #1, Kód prvku: SN07.03.0001; Object Layer Attributes #1, Podlaží: 1.NP; Object Layer Attributes #1, Požární odolnost: bez požadavku; Object Layer Attributes #1, Funkce (venkovní): Ne; Object Layer Attributes #1, Statická funkce: Ne; Object Layer Attributes #1, Vlhkostní namáhání oboustranné: Ne; Object Layer Attributes #1, Tloušťka opláštění: 2×12,5; Object Layer Attributes #1, Typ SDK desky: vysokopevnostní+bílá; Object Layer Attributes #1, Způsob opláštění: Jednostranné; Object Layer Attributes #1, Tloušťka izolace (2): 0; Object Layer Attributes #1, Objemová hmotnost izolace: 0; Object Layer Attributes #1, Typ profilu pro SDK: CW 100; Object Layer Attributes #1, Rozteč rastru: 625
SDK OPL. PROFESÍ/SDK OPL. BEZ PO | Půdorys 1.NP | SDK OPL. PROFESÍ/SDK OPL. BEZ PO 0.075 m |  | SDK OPL. PROFESÍ/SDK OPL. BEZ PO |  | 1464HWa1096312866 | m3 | Celá stěna | Nový | Suché stavební práce | SDK OPL. PROFESÍ/SDK OPL. BEZ PO | no | 1464Stě1096312869 | m3 | Stěna |  | 0.075 | 1.243 | 1.243 | 0.093 | 0.35 | 0.093 | 0.026 | 3.55 | NEMSOK - Object Layer Attributes #1, Kód prvku: SN07.03.0001; Object Layer Attributes #1, Podlaží: 1.NP; Object Layer Attributes #1, Požární odolnost: bez požadavku; Object Layer Attributes #1, Funkce (venkovní): Ne; Object Layer Attributes #1, Statická funkce: Ne; Object Layer Attributes #1, Vlhkostní namáhání oboustranné: Ne; Object Layer Attributes #1, Tloušťka opláštění: 2×12,5; Object Layer Attributes #1, Typ SDK desky: vysokopevnostní+bílá; Object Layer Attributes #1, Způsob opláštění: Jednostranné; Object Layer Attributes #1, Tloušťka izolace (2): 0; Object Layer Attributes #1, Objemová hmotnost izolace: 0; Object Layer Attributes #1, Typ profilu pro SDK: CW 100; Object Layer Attributes #1, Rozteč rastru: 625
SDK INSTAL. PŘDSTĚNA VYSOKÁ | Půdorys 1.NP | SDK INSTAL. PŘDSTĚNA VYSOKÁ 0.15 m |  | SDK INSTAL. PŘDSTĚNA VYSOKÁ |  | 1464HWa1096312876 | m3 | Celá stěna | Nový | Suché stavební práce | SDK INSTAL. PŘDSTĚNA VYSOKÁ | no | 1464Stě1096314687 | m3 | Stěna |  | 0.15 | 19.988 | 19.892 | 2.998 | 6.15 | 2.984 | 0.922 | 3.25 | NEMSOK - Object Layer Attributes #1, Kód prvku: SN07.03.0001; Object Layer Attributes #1, Podlaží: 1.NP; Object Layer Attributes #1, Požární odolnost: bez požadavku; Object Layer Attributes #1, Funkce (venkovní): Ne; Object Layer Attributes #1, Statická funkce: Ne; Object Layer Attributes #1, Vlhkostní namáhání oboustranné: Ne; Object Layer Attributes #1, Tloušťka opláštění: 2×12,5; Object Layer Attributes #1, Typ SDK desky: impregnovaná; Object Layer Attributes #1, Způsob opláštění: Jednostranné; Object Layer Attributes #1, Tloušťka izolace (2): 0; Object Layer Attributes #1, Objemová hmotnost izolace: 0; Object Layer Attributes #1, Typ profilu pro SDK: CW 100; Object Layer Attributes #1, Rozteč rastru: 625
SDK INSTAL. PŘDSTĚNA VYSOKÁ | Půdorys 1.NP | SDK INSTAL. PŘDSTĚNA VYSOKÁ 0.2 m |  | SDK INSTAL. PŘDSTĚNA VYSOKÁ |  | 1464HWa1096312879 | m3 | Celá stěna | Nový | Suché stavební práce | SDK INSTAL. PŘDSTĚNA VYSOKÁ | no | 1464Stě1096314040 | m3 | Stěna |  | 0.2 | 3.015 | 3.015 | 0.603 | 0.9 | 0.601 | 0.18 | 3.35 | NEMSOK - Object Layer Attributes #1, Kód prvku: SN07.03.0001; Object Layer Attributes #1, Podlaží: 1.NP; Object Layer Attributes #1, Požární odolnost: bez požadavku; Object Layer Attributes #1, Funkce (venkovní): Ne; Object Layer Attributes #1, Statická funkce: Ne; Object Layer Attributes #1, Vlhkostní namáhání oboustranné: Ne; Object Layer Attributes #1, Tloušťka opláštění: 2×12,5; Object Layer Attributes #1, Typ SDK desky: impregnovaná; Object Layer Attributes #1, Způsob opláštění: Jednostranné; Object Layer Attributes #1, Tloušťka izolace (2): 0; Object Layer Attributes #1, Objemová hmotnost izolace: 0; Object Layer Attributes #1, Typ profilu pro SDK: CW 100; Object Layer Attributes #1, Rozteč rastru: 625
SDK - 1 KCE + DVOJITÉ OPLÁŠTĚNÍ | Půdorys 1.NP | SDK - 1 KCE + DVOJITÉ OPLÁŠTĚNÍ 0.15 m |  | SDK - 1 KCE + DVOJITÉ OPLÁŠTĚNÍ |  | 1464HWa1096312891 | m3 | Celá stěna | Nový | Suché stavební práce | SDK - 1 KCE + DVOJITÉ OPLÁŠTĚNÍ | no | 1464Stě1096314180 | m3 | Stěna |  | 0.15 | 14.974 | 14.81 | 2.246 | 4.47 | 2.221 | 0.671 | 3.35 | NEMSOK - Object Layer Attributes #1, Kód prvku: SN07.03.0001; Object Layer Attributes #1, Podlaží: 1.NP; Object Layer Attributes #1, Požární odolnost: EI 60; Object Layer Attributes #1, Funkce (venkovní): Ne; Object Layer Attributes #1, Statická funkce: Ne; Object Layer Attributes #1, Vážená stavební neprůzvučnost: 54; Object Layer Attributes #1, Vlhkostní namáhání oboustranné: Ne; Object Layer Attributes #1, Tloušťka opláštění: 2×12,5; Object Layer Attributes #1, Typ SDK desky: vysokopevnostní+bílá; Object Layer Attributes #1, Způsob opláštění: Oboustranné; Object Layer Attributes #1, Tloušťka izolace (2): 100; Object Layer Attributes #1, Objemová hmotnost izolace: 25; Object Layer Attributes #1, Typ profilu pro SDK: CW 100; Object Layer Attributes #1, Rozteč rastru: 625
SDK - 1 KCE + DVOJITÉ OPLÁŠTĚNÍ | Půdorys 1.NP | SDK - 1 KCE + DVOJITÉ OPLÁŠTĚNÍ 0.15 m |  | SDK - 1 KCE + DVOJITÉ OPLÁŠTĚNÍ |  | 1464HWa1096312893 | m3 | Celá stěna | Nový | Suché stavební práce | SDK - 1 KCE + DVOJITÉ OPLÁŠTĚNÍ | no | 1464Stě1096312966 | m3 | Stěna |  | 0.15 | 3.35 | 3.35 | 0.502 | 1 | 0.502 | 0.15 | 3.35 | NEMSOK - Object Layer Attributes #1, Kód prvku: SN07.03.0001; Object Layer Attributes #1, Podlaží: 1.NP; Object Layer Attributes #1, Požární odolnost: EI 60; Object Layer Attributes #1, Funkce (venkovní): Ne; Object Layer Attributes #1, Statická funkce: Ne; Object Layer Attributes #1, Vážená stavební neprůzvučnost: 54; Object Layer Attributes #1, Vlhkostní namáhání oboustranné: Ne; Object Layer Attributes #1, Tloušťka opláštění: 2×12,5; Object Layer Attributes #1, Typ SDK desky: vysokopevnostní+bílá; Object Layer Attributes #1, Způsob opláštění: Oboustranné; Object Layer Attributes #1, Tloušťka izolace (2): 100; Object Layer Attributes #1, Objemová hmotnost izolace: 25; Object Layer Attributes #1, Typ profilu pro SDK: CW 100; Object Layer Attributes #1, Rozteč rastru: 625
SDK - 1 KCE + DVOJITÉ OPLÁŠTĚNÍ | Půdorys 1.NP | SDK - 1 KCE + DVOJITÉ OPLÁŠTĚNÍ 0.15 m |  | SDK - 1 KCE + DVOJITÉ OPLÁŠTĚNÍ |  | 1464HWa1096312896 | m3 | Celá stěna | Nový | Suché stavební práce | SDK - 1 KCE + DVOJITÉ OPLÁŠTĚNÍ | no | 1464Stě1096313573 | m3 | Stěna |  | 0.15 | 16.465 | 16.386 | 2.47 | 4.45 | 2.458 | 0.668 | 3.7 | NEMSOK - Object Layer Attributes #1, Kód prvku: SN07.03.0001; Object Layer Attributes #1, Podlaží: 1.NP; Object Layer Attributes #1, Požární odolnost: EI 60; Object Layer Attributes #1, Funkce (venkovní): Ne; Object Layer Attributes #1, Statická funkce: Ne; Object Layer Attributes #1, Vážená stavební neprůzvučnost: 54; Object Layer Attributes #1, Vlhkostní namáhání oboustranné: Ne; Object Layer Attributes #1, Tloušťka opláštění: 2×12,5; Object Layer Attributes #1, Typ SDK desky: vysokopevnostní+bílá; Object Layer Attributes #1, Způsob opláštění: Oboustranné; Object Layer Attributes #1, Tloušťka izolace (2): 100; Object Layer Attributes #1, Objemová hmotnost izolace: 25; Object Layer Attributes #1, Typ profilu pro SDK: CW 100; Object Layer Attributes #1, Rozteč rastru: 625
SDK - 1 KCE + DVOJITÉ OPLÁŠTĚNÍ | Půdorys 1.NP | SDK - 1 KCE + DVOJITÉ OPLÁŠTĚNÍ 0.125 m |  | SDK - 1 KCE + DVOJITÉ OPLÁŠTĚNÍ |  | 1464HWa1096312900 | m3 | Celá stěna | Nový | Suché stavební práce | SDK - 1 KCE + DVOJITÉ OPLÁŠTĚNÍ | no | 1464Stě1096313085 | m3 | Stěna |  | 0.125 | 5.695 | 5.695 | 0.712 | 1.7 | 0.712 | 0.212 | 3.35 | NEMSOK - Object Layer Attributes #1, Kód prvku: SN07.03.0001; Object Layer Attributes #1, Podlaží: 1.NP; Object Layer Attributes #1, Požární odolnost: EI 60; Object Layer Attributes #1, Funkce (venkovní): Ne; Object Layer Attributes #1, Statická funkce: Ne; Object Layer Attributes #1, Vážená stavební neprůzvučnost: 54; Object Layer Attributes #1, Vlhkostní namáhání oboustranné: Ne; Object Layer Attributes #1, Tloušťka opláštění: 2×12,5; Object Layer Attributes #1, Typ SDK desky: vysokopevnostní+bílá; Object Layer Attributes #1, Způsob opláštění: Oboustranné; Object Layer Attributes #1, Tloušťka izolace (2): 75; Object Layer Attributes #1, Objemová hmotnost izolace: 25; Object Layer Attributes #1, Typ profilu pro SDK: CW 75; Object Layer Attributes #1, Rozteč rastru: 625
SDK ŠACHTOVÁ STĚNA/SDK OPL. S PO | Půdorys 1.NP | SDK ŠACHTOVÁ STĚNA/SDK OPL. S PO 0.1 m |  | SDK ŠACHTOVÁ STĚNA/SDK OPL. S PO |  | 1464HWa1096312902 | m3 | Celá stěna | Nový | Suché stavební práce | SDK ŠACHTOVÁ STĚNA/SDK OPL. S PO | no | 1464Stě1096313599 | m3 | Stěna |  | 0.1 | 1.625 | 1.625 | 0.163 | 0.5 | 0.163 | 0.05 | 3.25 | NEMSOK - Object Layer Attributes #1, Kód prvku: SN07.03.0001; Object Layer Attributes #1, Podlaží: 1.NP; Object Layer Attributes #1, Požární odolnost: bez požadavku; Object Layer Attributes #1, Funkce (venkovní): Ne; Object Layer Attributes #1, Statická funkce: Ne; Object Layer Attributes #1, Vlhkostní namáhání oboustranné: Ne; Object Layer Attributes #1, Tloušťka opláštění: 2×12,5; Object Layer Attributes #1, Typ SDK desky: vysokopevnostní+bílá; Object Layer Attributes #1, Způsob opláštění: Jednostranné; Object Layer Attributes #1, Tloušťka izolace (2): 0; Object Layer Attributes #1, Objemová hmotnost izolace: 0; Object Layer Attributes #1, Typ profilu pro SDK: CW 75; Object Layer Attributes #1, Rozteč rastru: 625
SDK ŠACHTOVÁ STĚNA/SDK OPL. S PO | Půdorys 1.NP | SDK ŠACHTOVÁ STĚNA/SDK OPL. S PO 0.1 m |  | SDK ŠACHTOVÁ STĚNA/SDK OPL. S PO |  | 1464HWa1096312904 | m3 | Celá stěna | Nový | Suché stavební práce | SDK ŠACHTOVÁ STĚNA/SDK OPL. S PO | no | 1464Stě1096313242 | m3 | Stěna |  | 0.1 | 1.381 | 1.381 | 0.138 | 0.425 | 0.138 | 0.042 | 3.25 | NEMSOK - Object Layer Attributes #1, Kód prvku: SN07.03.0001; Object Layer Attributes #1, Podlaží: 1.NP; Object Layer Attributes #1, Požární odolnost: bez požadavku; Object Layer Attributes #1, Funkce (venkovní): Ne; Object Layer Attributes #1, Statická funkce: Ne; Object Layer Attributes #1, Vlhkostní namáhání oboustranné: Ne; Object Layer Attributes #1, Tloušťka opláštění: 2×12,5; Object Layer Attributes #1, Typ SDK desky: vysokopevnostní+bílá; Object Layer Attributes #1, Způsob opláštění: Jednostranné; Object Layer Attributes #1, Tloušťka izolace (2): 0; Object Layer Attributes #1, Objemová hmotnost izolace: 0; Object Layer Attributes #1, Typ profilu pro SDK: CW 75; Object Layer Attributes #1, Rozteč rastru: 625
SDK INSTAL. PŘDSTĚNA VYSOKÁ | Půdorys 1.NP | SDK INSTAL. PŘDSTĚNA VYSOKÁ 0.2 m |  | SDK INSTAL. PŘDSTĚNA VYSOKÁ |  | 1464HWa1096312905 | m3 | Celá stěna | Nový | Suché stavební práce | SDK INSTAL. PŘDSTĚNA VYSOKÁ | no | 1464Stě1096313094 | m3 | Stěna |  | 0.2 | 3.819 | 3.819 | 0.764 | 1.175 | 0.764 | 0.235 | 3.25 | NEMSOK - Object Layer Attributes #1, Kód prvku: SN07.03.0001; Object Layer Attributes #1, Podlaží: 1.NP; Object Layer Attributes #1, Požární odolnost: bez požadavku; Object Layer Attributes #1, Funkce (venkovní): Ne; Object Layer Attributes #1, Statická funkce: Ne; Object Layer Attributes #1, Vlhkostní namáhání oboustranné: Ne; Object Layer Attributes #1, Tloušťka opláštění: 2×12,5; Object Layer Attributes #1, Typ SDK desky: impregnovaná; Object Layer Attributes #1, Způsob opláštění: Jednostranné; Object Layer Attributes #1, Tloušťka izolace (2): 0; Object Layer Attributes #1, Objemová hmotnost izolace: 0; Object Layer Attributes #1, Typ profilu pro SDK: CW 100; Object Layer Attributes #1, Rozteč rastru: 625
SDK OPL. PROFESÍ/SDK OPL. BEZ PO | Půdorys 1.NP | SDK OPL. PROFESÍ/SDK OPL. BEZ PO 0.075 m |  | SDK OPL. PROFESÍ/SDK OPL. BEZ PO |  | 1464HWa1096312908 | m3 | Celá stěna | Nový | Suché stavební práce | SDK OPL. PROFESÍ/SDK OPL. BEZ PO | no | 1464Stě1096312910 | m3 | Stěna |  | 0.075 | 1.462 | 1.463 | 0.11 | 0.45 | 0.11 | 0.034 | 3.25 | NEMSOK - Object Layer Attributes #1, Kód prvku: SN07.03.0001; Object Layer Attributes #1, Podlaží: 1.NP; Object Layer Attributes #1, Požární odolnost: bez požadavku; Object Layer Attributes #1, Funkce (venkovní): Ne; Object Layer Attributes #1, Statická funkce: Ne; Object Layer Attributes #1, Vlhkostní namáhání oboustranné: Ne; Object Layer Attributes #1, Tloušťka opláštění: 2×12,5; Object Layer Attributes #1, Typ SDK desky: vysokopevnostní+bílá; Object Layer Attributes #1, Způsob opláštění: Jednostranné; Object Layer Attributes #1, Tloušťka izolace (2): 0; Object Layer Attributes #1, Objemová hmotnost izolace: 0; Object Layer Attributes #1, Typ profilu pro SDK: CW 100; Object Layer Attributes #1, Rozteč rastru: 625
SDK - 1 KCE + DVOJITÉ OPLÁŠTĚNÍ | Půdorys 1.NP | SDK - 1 KCE + DVOJITÉ OPLÁŠTĚNÍ 0.125 m |  | SDK - 1 KCE + DVOJITÉ OPLÁŠTĚNÍ |  | 1464HWa1096312916 | m3 | Celá stěna | Nový | Suché stavební práce | SDK - 1 KCE + DVOJITÉ OPLÁŠTĚNÍ | no | 1464Stě1096313721 | m3 | Stěna |  | 0.125 | 8.291 | 6.312 | 1.036 | 2.475 | 0.789 | 0.309 | 3.35 | NEMSOK - Object Layer Attributes #1, Kód prvku: SN07.03.0001; Object Layer Attributes #1, Podlaží: 1.NP; Object Layer Attributes #1, Požární odolnost: EI 60; Object Layer Attributes #1, Funkce (venkovní): Ne; Object Layer Attributes #1, Statická funkce: Ne; Object Layer Attributes #1, Vážená stavební neprůzvučnost: 54; Object Layer Attributes #1, Vlhkostní namáhání oboustranné: Ne; Object Layer Attributes #1, Tloušťka opláštění: 2×12,5; Object Layer Attributes #1, Typ SDK desky: vysokopevnostní+bílá; Object Layer Attributes #1, Způsob opláštění: Oboustranné; Object Layer Attributes #1, Tloušťka izolace (2): 75; Object Layer Attributes #1, Objemová hmotnost izolace: 25; Object Layer Attributes #1, Typ profilu pro SDK: CW 75; Object Layer Attributes #1, Rozteč rastru: 625
SDK - 1 KCE + DVOJITÉ OPLÁŠTĚNÍ | Půdorys 1.NP | SDK - 1 KCE + DVOJITÉ OPLÁŠTĚNÍ 0.125 m |  | SDK - 1 KCE + DVOJITÉ OPLÁŠTĚNÍ |  | 1464HWa1096312917 | m3 | Celá stěna | Nový | Suché stavební práce | SDK - 1 KCE + DVOJITÉ OPLÁŠTĚNÍ | no | 1464Stě1096313717 | m3 | Stěna |  | 0.125 | 2.925 | 0 | 0.366 | 0.9 | 0 | 0.113 | 3.25 | NEMSOK - Object Layer Attributes #1, Kód prvku: SN07.03.0001; Object Layer Attributes #1, Podlaží: 1.NP; Object Layer Attributes #1, Požární odolnost: EI 60; Object Layer Attributes #1, Funkce (venkovní): Ne; Object Layer Attributes #1, Statická funkce: Ne; Object Layer Attributes #1, Vážená stavební neprůzvučnost: 54; Object Layer Attributes #1, Vlhkostní namáhání oboustranné: Ne; Object Layer Attributes #1, Tloušťka opláštění: 2×12,5; Object Layer Attributes #1, Typ SDK desky: vysokopevnostní+bílá; Object Layer Attributes #1, Způsob opláštění: Oboustranné; Object Layer Attributes #1, Tloušťka izolace (2): 75; Object Layer Attributes #1, Objemová hmotnost izolace: 25; Object Layer Attributes #1, Typ profilu pro SDK: CW 75; Object Layer Attributes #1, Rozteč rastru: 625
SDK INSTAL. PŘDSTĚNA VYSOKÁ | Půdorys 1.NP | SDK INSTAL. PŘDSTĚNA VYSOKÁ 0.1 m |  | SDK INSTAL. PŘDSTĚNA VYSOKÁ |  | 1464HWa1096312931 | m3 | Celá stěna | Nový | Suché stavební práce | SDK INSTAL. PŘDSTĚNA VYSOKÁ | no | 1464Stě1096314691 | m3 | Stěna |  | 0.1 | 9.054 | 9.055 | 0.905 | 2.786 | 0.905 | 0.279 | 3.25 | NEMSOK - Object Layer Attributes #1, Kód prvku: SN07.03.0001; Object Layer Attributes #1, Podlaží: 1.NP; Object Layer Attributes #1, Požární odolnost: bez požadavku; Object Layer Attributes #1, Funkce (venkovní): Ne; Object Layer Attributes #1, Statická funkce: Ne; Object Layer Attributes #1, Vlhkostní namáhání oboustranné: Ne; Object Layer Attributes #1, Tloušťka opláštění: 2×12,5; Object Layer Attributes #1, Typ SDK desky: impregnovaná; Object Layer Attributes #1, Způsob opláštění: Jednostranné; Object Layer Attributes #1, Tloušťka izolace (2): 0; Object Layer Attributes #1, Objemová hmotnost izolace: 0; Object Layer Attributes #1, Typ profilu pro SDK: CW 75; Object Layer Attributes #1, Rozteč rastru: 625
SDK OPL. PROFESÍ/SDK OPL. BEZ PO | Půdorys 1.NP | SDK OPL. PROFESÍ/SDK OPL. BEZ PO 0.075 m |  | SDK OPL. PROFESÍ/SDK OPL. BEZ PO |  | 1464HWa1096312933 | m3 | Celá stěna | Nový | Suché stavební práce | SDK OPL. PROFESÍ/SDK OPL. BEZ PO | no | 1464Stě1096312946 | m3 | Stěna |  | 0.075 | 0.829 | 0.829 | 0.062 | 0.255 | 0.062 | 0.019 | 3.25 | NEMSOK - Object Layer Attributes #1, Kód prvku: SN07.03.0001; Object Layer Attributes #1, Podlaží: 1.NP; Object Layer Attributes #1, Požární odolnost: bez požadavku; Object Layer Attributes #1, Funkce (venkovní): Ne; Object Layer Attributes #1, Statická funkce: Ne; Object Layer Attributes #1, Vlhkostní namáhání oboustranné: Ne; Object Layer Attributes #1, Tloušťka opláštění: 2×12,5; Object Layer Attributes #1, Typ SDK desky: vysokopevnostní+bílá; Object Layer Attributes #1, Způsob opláštění: Jednostranné; Object Layer Attributes #1, Tloušťka izolace (2): 0; Object Layer Attributes #1, Objemová hmotnost izolace: 0; Object Layer Attributes #1, Typ profilu pro SDK: CW 100; Object Layer Attributes #1, Rozteč rastru: 625
SDK OPL. PROFESÍ/SDK OPL. BEZ PO | Půdorys 1.NP | SDK OPL. PROFESÍ/SDK OPL. BEZ PO 0.075 m |  | SDK OPL. PROFESÍ/SDK OPL. BEZ PO |  | 1464HWa1096312935 | m3 | Celá stěna | Nový | Suché stavební práce | SDK OPL. PROFESÍ/SDK OPL. BEZ PO | no | 1464Stě1096312948 | m3 | Stěna |  | 0.075 | 3.575 | 3.575 | 0.268 | 1.1 | 0.268 | 0.083 | 3.25 | NEMSOK - Object Layer Attributes #1, Kód prvku: SN07.03.0001; Object Layer Attributes #1, Podlaží: 1.NP; Object Layer Attributes #1, Požární odolnost: bez požadavku; Object Layer Attributes #1, Funkce (venkovní): Ne; Object Layer Attributes #1, Statická funkce: Ne; Object Layer Attributes #1, Vlhkostní namáhání oboustranné: Ne; Object Layer Attributes #1, Tloušťka opláštění: 2×12,5; Object Layer Attributes #1, Typ SDK desky: vysokopevnostní+bílá; Object Layer Attributes #1, Způsob opláštění: Jednostranné; Object Layer Attributes #1, Tloušťka izolace (2): 0; Object Layer Attributes #1, Objemová hmotnost izolace: 0; Object Layer Attributes #1, Typ profilu pro SDK: CW 100; Object Layer Attributes #1, Rozteč rastru: 625
SDK OPL. PROFESÍ/SDK OPL. BEZ PO | Půdorys 1.NP | SDK OPL. PROFESÍ/SDK OPL. BEZ PO 0.075 m |  | SDK OPL. PROFESÍ/SDK OPL. BEZ PO |  | 1464HWa1096312937 | m3 | Celá stěna | Nový | Suché stavební práce | SDK OPL. PROFESÍ/SDK OPL. BEZ PO | no | 1464Stě1096312942 | m3 | Stěna |  | 0.075 | 17.534 | 17.534 | 1.315 | 5.395 | 1.315 | 0.405 | 3.25 | NEMSOK - Object Layer Attributes #1, Kód prvku: SN07.03.0001; Object Layer Attributes #1, Podlaží: 1.NP; Object Layer Attributes #1, Požární odolnost: bez požadavku; Object Layer Attributes #1, Funkce (venkovní): Ne; Object Layer Attributes #1, Statická funkce: Ne; Object Layer Attributes #1, Vlhkostní namáhání oboustranné: Ne; Object Layer Attributes #1, Tloušťka opláštění: 2×12,5; Object Layer Attributes #1, Typ SDK desky: vysokopevnostní+bílá; Object Layer Attributes #1, Způsob opláštění: Jednostranné; Object Layer Attributes #1, Tloušťka izolace (2): 0; Object Layer Attributes #1, Objemová hmotnost izolace: 0; Object Layer Attributes #1, Typ profilu pro SDK: CW 100; Object Layer Attributes #1, Rozteč rastru: 625
SDK OPL. PROFESÍ/SDK OPL. BEZ PO | Půdorys 1.NP | SDK OPL. PROFESÍ/SDK OPL. BEZ PO 0.075 m |  | SDK OPL. PROFESÍ/SDK OPL. BEZ PO |  | 1464HWa1096312938 | m3 | Celá stěna | Nový | Suché stavební práce | SDK OPL. PROFESÍ/SDK OPL. BEZ PO | no | 1464Stě1096314728 | m3 | Stěna |  | 0.075 | 2.6 | 2.6 | 0.195 | 0.8 | 0.195 | 0.06 | 3.25 | NEMSOK - Object Layer Attributes #1, Kód prvku: SN07.03.0001; Object Layer Attributes #1, Podlaží: 1.NP; Object Layer Attributes #1, Požární odolnost: bez požadavku; Object Layer Attributes #1, Funkce (venkovní): Ne; Object Layer Attributes #1, Statická funkce: Ne; Object Layer Attributes #1, Vlhkostní namáhání oboustranné: Ne; Object Layer Attributes #1, Tloušťka opláštění: 2×12,5; Object Layer Attributes #1, Typ SDK desky: vysokopevnostní+bílá; Object Layer Attributes #1, Způsob opláštění: Jednostranné; Object Layer Attributes #1, Tloušťka izolace (2): 0; Object Layer Attributes #1, Objemová hmotnost izolace: 0; Object Layer Attributes #1, Typ profilu pro SDK: CW 100; Object Layer Attributes #1, Rozteč rastru: 625
SDK OPL. PROFESÍ/SDK OPL. BEZ PO | Půdorys 1.NP | SDK OPL. PROFESÍ/SDK OPL. BEZ PO 0.075 m |  | SDK OPL. PROFESÍ/SDK OPL. BEZ PO |  | 1464HWa1096312943 | m3 | Celá stěna | Nový | Suché stavební práce | SDK OPL. PROFESÍ/SDK OPL. BEZ PO | no | 1464Stě1096314693 | m3 | Stěna |  | 0.075 | 8.288 | 8.288 | 0.622 | 2.55 | 0.622 | 0.191 | 3.25 | NEMSOK - Object Layer Attributes #1, Kód prvku: SN07.03.0001; Object Layer Attributes #1, Podlaží: 1.NP; Object Layer Attributes #1, Požární odolnost: bez požadavku; Object Layer Attributes #1, Funkce (venkovní): Ne; Object Layer Attributes #1, Statická funkce: Ne; Object Layer Attributes #1, Vlhkostní namáhání oboustranné: Ne; Object Layer Attributes #1, Tloušťka opláštění: 2×12,5; Object Layer Attributes #1, Typ SDK desky: vysokopevnostní+bílá; Object Layer Attributes #1, Způsob opláštění: Jednostranné; Object Layer Attributes #1, Tloušťka izolace (2): 0; Object Layer Attributes #1, Objemová hmotnost izolace: 0; Object Layer Attributes #1, Typ profilu pro SDK: CW 100; Object Layer Attributes #1, Rozteč rastru: 625
SDK OPL. PROFESÍ/SDK OPL. BEZ PO | Půdorys 1.NP | SDK OPL. PROFESÍ/SDK OPL. BEZ PO 0.075 m |  | SDK OPL. PROFESÍ/SDK OPL. BEZ PO |  | 1464HWa1096312949 | m3 | Celá stěna | Nový | Suché stavební práce | SDK OPL. PROFESÍ/SDK OPL. BEZ PO | no | 1464Stě1096314689 | m3 | Stěna |  | 0.075 | 6.663 | 6.663 | 0.5 | 2.05 | 0.5 | 0.154 | 3.25 | NEMSOK - Object Layer Attributes #1, Kód prvku: SN07.03.0001; Object Layer Attributes #1, Podlaží: 1.NP; Object Layer Attributes #1, Požární odolnost: bez požadavku; Object Layer Attributes #1, Funkce (venkovní): Ne; Object Layer Attributes #1, Statická funkce: Ne; Object Layer Attributes #1, Vlhkostní namáhání oboustranné: Ne; Object Layer Attributes #1, Tloušťka opláštění: 2×12,5; Object Layer Attributes #1, Typ SDK desky: vysokopevnostní+bílá; Object Layer Attributes #1, Způsob opláštění: Jednostranné; Object Layer Attributes #1, Tloušťka izolace (2): 0; Object Layer Attributes #1, Objemová hmotnost izolace: 0; Object Layer Attributes #1, Typ profilu pro SDK: CW 100; Object Layer Attributes #1, Rozteč rastru: 625
SDK OPL. PROFESÍ/SDK OPL. BEZ PO | Půdorys 1.NP | SDK OPL. PROFESÍ/SDK OPL. BEZ PO 0.075 m |  | SDK OPL. PROFESÍ/SDK OPL. BEZ PO |  | 1464HWa1096312951 | m3 | Celá stěna | Nový | Suché stavební práce | SDK OPL. PROFESÍ/SDK OPL. BEZ PO | no | 1464Stě1096314486 | m3 | Stěna |  | 0.075 | 6.5 | 6.5 | 0.488 | 2 | 0.488 | 0.15 | 3.25 | NEMSOK - Object Layer Attributes #1, Kód prvku: SN07.03.0001; Object Layer Attributes #1, Podlaží: 1.NP; Object Layer Attributes #1, Požární odolnost: bez požadavku; Object Layer Attributes #1, Funkce (venkovní): Ne; Object Layer Attributes #1, Statická funkce: Ne; Object Layer Attributes #1, Vlhkostní namáhání oboustranné: Ne; Object Layer Attributes #1, Tloušťka opláštění: 2×12,5; Object Layer Attributes #1, Typ SDK desky: vysokopevnostní+bílá; Object Layer Attributes #1, Způsob opláštění: Jednostranné; Object Layer Attributes #1, Tloušťka izolace (2): 0; Object Layer Attributes #1, Objemová hmotnost izolace: 0; Object Layer Attributes #1, Typ profilu pro SDK: CW 100; Object Layer Attributes #1, Rozteč rastru: 625
SDK - 1 KCE + DVOJITÉ OPLÁŠTĚNÍ | Půdorys 1.NP | SDK - 1 KCE + DVOJITÉ OPLÁŠTĚNÍ 0.125 m |  | SDK - 1 KCE + DVOJITÉ OPLÁŠTĚNÍ |  | 1464HWa1096312953 | m3 | Celá stěna | Nový | Suché stavební práce | SDK - 1 KCE + DVOJITÉ OPLÁŠTĚNÍ | no | 1464Stě1096312961 | m3 | Stěna |  | 0.125 | 3.182 | 3.183 | 0.398 | 0.95 | 0.398 | 0.119 | 3.35 | NEMSOK - Object Layer Attributes #1, Kód prvku: SN07.03.0001; Object Layer Attributes #1, Podlaží: 1.NP; Object Layer Attributes #1, Požární odolnost: EI 60; Object Layer Attributes #1, Funkce (venkovní): Ne; Object Layer Attributes #1, Statická funkce: Ne; Object Layer Attributes #1, Vážená stavební neprůzvučnost: 54; Object Layer Attributes #1, Vlhkostní namáhání oboustranné: Ne; Object Layer Attributes #1, Tloušťka opláštění: 2×12,5; Object Layer Attributes #1, Typ SDK desky: vysokopevnostní+bílá; Object Layer Attributes #1, Způsob opláštění: Oboustranné; Object Layer Attributes #1, Tloušťka izolace (2): 75; Object Layer Attributes #1, Objemová hmotnost izolace: 25; Object Layer Attributes #1, Typ profilu pro SDK: CW 75; Object Layer Attributes #1, Rozteč rastru: 625
SDK - 1 KCE + DVOJITÉ OPLÁŠTĚNÍ | Půdorys 1.NP | SDK - 1 KCE + DVOJITÉ OPLÁŠTĚNÍ 0.125 m |  | SDK - 1 KCE + DVOJITÉ OPLÁŠTĚNÍ |  | 1464HWa1096312955 | m3 | Celá stěna | Nový | Suché stavební práce | SDK - 1 KCE + DVOJITÉ OPLÁŠTĚNÍ | no | 1464Stě1096312964 | m3 | Stěna |  | 0.125 | 2.01 | 2.01 | 0.251 | 0.6 | 0.251 | 0.075 | 3.35 | NEMSOK - Object Layer Attributes #1, Kód prvku: SN07.03.0001; Object Layer Attributes #1, Podlaží: 1.NP; Object Layer Attributes #1, Požární odolnost: EI 60; Object Layer Attributes #1, Funkce (venkovní): Ne; Object Layer Attributes #1, Statická funkce: Ne; Object Layer Attributes #1, Vážená stavební neprůzvučnost: 54; Object Layer Attributes #1, Vlhkostní namáhání oboustranné: Ne; Object Layer Attributes #1, Tloušťka opláštění: 2×12,5; Object Layer Attributes #1, Typ SDK desky: vysokopevnostní+bílá; Object Layer Attributes #1, Způsob opláštění: Oboustranné; Object Layer Attributes #1, Tloušťka izolace (2): 75; Object Layer Attributes #1, Objemová hmotnost izolace: 25; Object Layer Attributes #1, Typ profilu pro SDK: CW 75; Object Layer Attributes #1, Rozteč rastru: 625
SDK - 1 KCE + DVOJITÉ OPLÁŠTĚNÍ | Půdorys 1.NP | SDK - 1 KCE + DVOJITÉ OPLÁŠTĚNÍ 0.125 m |  | SDK - 1 KCE + DVOJITÉ OPLÁŠTĚNÍ |  | 1464HWa1096312959 | m3 | Celá stěna | Nový | Suché stavební práce | SDK - 1 KCE + DVOJITÉ OPLÁŠTĚNÍ | no | 1464Stě1096314163 | m3 | Stěna |  | 0.125 | 25.46 | 23.475 | 3.183 | 7.6 | 2.934 | 0.95 | 3.35 | NEMSOK - Object Layer Attributes #1, Kód prvku: SN07.03.0001; Object Layer Attributes #1, Podlaží: 1.NP; Object Layer Attributes #1, Požární odolnost: EI 60; Object Layer Attributes #1, Funkce (venkovní): Ne; Object Layer Attributes #1, Statická funkce: Ne; Object Layer Attributes #1, Vážená stavební neprůzvučnost: 54; Object Layer Attributes #1, Vlhkostní namáhání oboustranné: Ne; Object Layer Attributes #1, Tloušťka opláštění: 2×12,5; Object Layer Attributes #1, Typ SDK desky: vysokopevnostní+bílá; Object Layer Attributes #1, Způsob opláštění: Oboustranné; Object Layer Attributes #1, Tloušťka izolace (2): 75; Object Layer Attributes #1, Objemová hmotnost izolace: 25; Object Layer Attributes #1, Typ profilu pro SDK: CW 75; Object Layer Attributes #1, Rozteč rastru: 625
SDK - 1 KCE + DVOJITÉ OPLÁŠTĚNÍ | Půdorys 1.NP | SDK - 1 KCE + DVOJITÉ OPLÁŠTĚNÍ 0.1 m |  | SDK - 1 KCE + DVOJITÉ OPLÁŠTĚNÍ |  | 1464HWa1096313003 | m3 | Celá stěna | Nový | Suché stavební práce | SDK - 1 KCE + DVOJITÉ OPLÁŠTĚNÍ | no | 1464Stě1096314440 | m3 | Stěna |  | 0.1 | 6.479 | 6.383 | 0.648 | 1.825 | 0.638 | 0.182 | 3.55 | NEMSOK - Object Layer Attributes #1, Kód prvku: SN07.03.0001; Object Layer Attributes #1, Podlaží: 1.NP; Object Layer Attributes #1, Požární odolnost: EI 60; Object Layer Attributes #1, Funkce (venkovní): Ne; Object Layer Attributes #1, Statická funkce: Ne; Object Layer Attributes #1, Vážená stavební neprůzvučnost: 54; Object Layer Attributes #1, Vlhkostní namáhání oboustranné: Ne; Object Layer Attributes #1, Tloušťka opláštění: 2×12,5; Object Layer Attributes #1, Typ SDK desky: vysokopevnostní+bílá; Object Layer Attributes #1, Způsob opláštění: Oboustranné; Object Layer Attributes #1, Tloušťka izolace (2): 50; Object Layer Attributes #1, Objemová hmotnost izolace: 25; Object Layer Attributes #1, Typ profilu pro SDK: CW 50; Object Layer Attributes #1, Rozteč rastru: 625
SDK - 1 KCE + DVOJITÉ OPLÁŠTĚNÍ | Půdorys 1.NP | SDK - 1 KCE + DVOJITÉ OPLÁŠTĚNÍ 0.1 m |  | SDK - 1 KCE + DVOJITÉ OPLÁŠTĚNÍ |  | 1464HWa1096313006 | m3 | Celá stěna | Nový | Suché stavební práce | SDK - 1 KCE + DVOJITÉ OPLÁŠTĚNÍ | no | 1464Stě1096314370 | m3 | Stěna |  | 0.1 | 12.247 | 9.718 | 1.225 | 3.45 | 0.972 | 0.345 | 3.55 | NEMSOK - Object Layer Attributes #1, Kód prvku: SN07.03.0001; Object Layer Attributes #1, Podlaží: 1.NP; Object Layer Attributes #1, Požární odolnost: EI 60; Object Layer Attributes #1, Funkce (venkovní): Ne; Object Layer Attributes #1, Statická funkce: Ne; Object Layer Attributes #1, Vážená stavební neprůzvučnost: 54; Object Layer Attributes #1, Vlhkostní namáhání oboustranné: Ne; Object Layer Attributes #1, Tloušťka opláštění: 2×12,5; Object Layer Attributes #1, Typ SDK desky: vysokopevnostní+bílá; Object Layer Attributes #1, Způsob opláštění: Oboustranné; Object Layer Attributes #1, Tloušťka izolace (2): 50; Object Layer Attributes #1, Objemová hmotnost izolace: 25; Object Layer Attributes #1, Typ profilu pro SDK: CW 50; Object Layer Attributes #1, Rozteč rastru: 625
SDK - 1 KCE + DVOJITÉ OPLÁŠTĚNÍ | Půdorys 1.NP | SDK - 1 KCE + DVOJITÉ OPLÁŠTĚNÍ 0.125 m |  | SDK - 1 KCE + DVOJITÉ OPLÁŠTĚNÍ |  | 1464HWa1096313016 | m3 | Celá stěna | Nový | Suché stavební práce | SDK - 1 KCE + DVOJITÉ OPLÁŠTĚNÍ | no | 1464Stě1096314423 | m3 | Stěna |  | 0.125 | 11.893 | 6.469 | 1.487 | 3.35 | 0.809 | 0.419 | 3.55 | NEMSOK - Object Layer Attributes #1, Kód prvku: SN07.03.0001; Object Layer Attributes #1, Podlaží: 1.NP; Object Layer Attributes #1, Požární odolnost: EI 60; Object Layer Attributes #1, Funkce (venkovní): Ne; Object Layer Attributes #1, Statická funkce: Ne; Object Layer Attributes #1, Vážená stavební neprůzvučnost: 54; Object Layer Attributes #1, Vlhkostní namáhání oboustranné: Ne; Object Layer Attributes #1, Tloušťka opláštění: 2×12,5; Object Layer Attributes #1, Typ SDK desky: vysokopevnostní+bílá; Object Layer Attributes #1, Způsob opláštění: Oboustranné; Object Layer Attributes #1, Tloušťka izolace (2): 75; Object Layer Attributes #1, Objemová hmotnost izolace: 25; Object Layer Attributes #1, Typ profilu pro SDK: CW 75; Object Layer Attributes #1, Rozteč rastru: 625
SDK - 1 KCE + DVOJITÉ OPLÁŠTĚNÍ | Půdorys 1.NP | SDK - 1 KCE + DVOJITÉ OPLÁŠTĚNÍ 0.1 m |  | SDK - 1 KCE + DVOJITÉ OPLÁŠTĚNÍ |  | 1464HWa1096313034 | m3 | Celá stěna | Nový | Suché stavební práce | SDK - 1 KCE + DVOJITÉ OPLÁŠTĚNÍ | no | 1464Stě1096313055 | m3 | Stěna |  | 0.1 | 7.454 | 7.454 | 0.745 | 2.225 | 0.745 | 0.222 | 3.35 | NEMSOK - Object Layer Attributes #1, Kód prvku: SN07.03.0001; Object Layer Attributes #1, Podlaží: 1.NP; Object Layer Attributes #1, Požární odolnost: EI 60; Object Layer Attributes #1, Funkce (venkovní): Ne; Object Layer Attributes #1, Statická funkce: Ne; Object Layer Attributes #1, Vážená stavební neprůzvučnost: 54; Object Layer Attributes #1, Vlhkostní namáhání oboustranné: Ne; Object Layer Attributes #1, Tloušťka opláštění: 2×12,5; Object Layer Attributes #1, Typ SDK desky: vysokopevnostní+bílá; Object Layer Attributes #1, Způsob opláštění: Oboustranné; Object Layer Attributes #1, Tloušťka izolace (2): 50; Object Layer Attributes #1, Objemová hmotnost izolace: 25; Object Layer Attributes #1, Typ profilu pro SDK: CW 50; Object Layer Attributes #1, Rozteč rastru: 625
SDK - 1 KCE + DVOJITÉ OPLÁŠTĚNÍ | Půdorys 1.NP | SDK - 1 KCE + DVOJITÉ OPLÁŠTĚNÍ 0.125 m |  | SDK - 1 KCE + DVOJITÉ OPLÁŠTĚNÍ |  | 1464HWa1096313036 | m3 | Celá stěna | Nový | Suché stavební práce | SDK - 1 KCE + DVOJITÉ OPLÁŠTĚNÍ | no | 1464Stě1096313750 | m3 | Stěna |  | 0.125 | 22.378 | 20.288 | 2.797 | 6.68 | 2.586 | 0.835 | 3.35 | NEMSOK - Object Layer Attributes #1, Kód prvku: SN07.03.0001; Object Layer Attributes #1, Podlaží: 1.NP; Object Layer Attributes #1, Požární odolnost: EI 60; Object Layer Attributes #1, Funkce (venkovní): Ne; Object Layer Attributes #1, Statická funkce: Ne; Object Layer Attributes #1, Vážená stavební neprůzvučnost: 54; Object Layer Attributes #1, Vlhkostní namáhání oboustranné: Ne; Object Layer Attributes #1, Tloušťka opláštění: 2×12,5; Object Layer Attributes #1, Typ SDK desky: vysokopevnostní+bílá; Object Layer Attributes #1, Způsob opláštění: Oboustranné; Object Layer Attributes #1, Tloušťka izolace (2): 75; Object Layer Attributes #1, Objemová hmotnost izolace: 25; Object Layer Attributes #1, Typ profilu pro SDK: CW 75; Object Layer Attributes #1, Rozteč rastru: 625
SDK - 1 KCE + DVOJITÉ OPLÁŠTĚNÍ | Půdorys 1.NP | SDK - 1 KCE + DVOJITÉ OPLÁŠTĚNÍ 0.125 m |  | SDK - 1 KCE + DVOJITÉ OPLÁŠTĚNÍ |  | 1464HWa1096313052 | m3 | Celá stěna | Nový | Suché stavební práce | SDK - 1 KCE + DVOJITÉ OPLÁŠTĚNÍ | no | 1464Stě1096313809 | m3 | Stěna |  | 0.125 | 12.395 | 8.573 | 1.549 | 3.7 | 1.072 | 0.462 | 3.35 | NEMSOK - Object Layer Attributes #1, Kód prvku: SN07.03.0001; Object Layer Attributes #1, Podlaží: 1.NP; Object Layer Attributes #1, Požární odolnost: EI 60; Object Layer Attributes #1, Funkce (venkovní): Ne; Object Layer Attributes #1, Statická funkce: Ne; Object Layer Attributes #1, Vážená stavební neprůzvučnost: 54; Object Layer Attributes #1, Vlhkostní namáhání oboustranné: Ne; Object Layer Attributes #1, Tloušťka opláštění: 2×12,5; Object Layer Attributes #1, Typ SDK desky: vysokopevnostní+bílá; Object Layer Attributes #1, Způsob opláštění: Oboustranné; Object Layer Attributes #1, Tloušťka izolace (2): 75; Object Layer Attributes #1, Objemová hmotnost izolace: 25; Object Layer Attributes #1, Typ profilu pro SDK: CW 75; Object Layer Attributes #1, Rozteč rastru: 625
SDK INSTAL. PŘDSTĚNA VYSOKÁ | Půdorys 1.NP | SDK INSTAL. PŘDSTĚNA VYSOKÁ 0.25 m |  | SDK INSTAL. PŘDSTĚNA VYSOKÁ |  | 1464HWa1096313060 | m3 | Celá stěna | Nový | Suché stavební práce | SDK INSTAL. PŘDSTĚNA VYSOKÁ | no | 1464Stě1096313083 | m3 | Stěna |  | 0.25 | 3.25 | 3.25 | 0.813 | 1 | 0.813 | 0.25 | 3.25 | NEMSOK - Object Layer Attributes #1, Kód prvku: SN07.03.0001; Object Layer Attributes #1, Podlaží: 1.NP; Object Layer Attributes #1, Požární odolnost: bez požadavku; Object Layer Attributes #1, Funkce (venkovní): Ne; Object Layer Attributes #1, Statická funkce: Ne; Object Layer Attributes #1, Vlhkostní namáhání oboustranné: Ne; Object Layer Attributes #1, Tloušťka opláštění: 2×12,5; Object Layer Attributes #1, Typ SDK desky: impregnovaná; Object Layer Attributes #1, Způsob opláštění: Jednostranné; Object Layer Attributes #1, Tloušťka izolace (2): 0; Object Layer Attributes #1, Objemová hmotnost izolace: 0; Object Layer Attributes #1, Typ profilu pro SDK: CW 100; Object Layer Attributes #1, Rozteč rastru: 625
SDK - 1 KCE + DVOJITÉ OPLÁŠTĚNÍ | Půdorys 1.NP | SDK - 1 KCE + DVOJITÉ OPLÁŠTĚNÍ 0.125 m |  | SDK - 1 KCE + DVOJITÉ OPLÁŠTĚNÍ |  | 1464HWa1096313061 | m3 | Celá stěna | Nový | Suché stavební práce | SDK - 1 KCE + DVOJITÉ OPLÁŠTĚNÍ | no | 1464Stě1096313698 | m3 | Stěna |  | 0.125 | 22.713 | 10.125 | 2.839 | 6.78 | 1.255 | 0.847 | 3.35 | NEMSOK - Object Layer Attributes #1, Kód prvku: SN07.03.0001; Object Layer Attributes #1, Podlaží: 1.NP; Object Layer Attributes #1, Požární odolnost: EI 60; Object Layer Attributes #1, Funkce (venkovní): Ne; Object Layer Attributes #1, Statická funkce: Ne; Object Layer Attributes #1, Vážená stavební neprůzvučnost: 54; Object Layer Attributes #1, Vlhkostní namáhání oboustranné: Ne; Object Layer Attributes #1, Tloušťka opláštění: 2×12,5; Object Layer Attributes #1, Typ SDK desky: vysokopevnostní+bílá; Object Layer Attributes #1, Způsob opláštění: Oboustranné; Object Layer Attributes #1, Tloušťka izolace (2): 75; Object Layer Attributes #1, Objemová hmotnost izolace: 25; Object Layer Attributes #1, Typ profilu pro SDK: CW 75; Object Layer Attributes #1, Rozteč rastru: 625
SDK - 1 KCE + DVOJITÉ OPLÁŠTĚNÍ | Půdorys 1.NP | SDK - 1 KCE + DVOJITÉ OPLÁŠTĚNÍ 0.1 m |  | SDK - 1 KCE + DVOJITÉ OPLÁŠTĚNÍ |  | 1464HWa1096313064 | m3 | Celá stěna | Nový | Suché stavební práce | SDK - 1 KCE + DVOJITÉ OPLÁŠTĚNÍ | no | 1464Stě1096313634 | m3 | Stěna |  | 0.1 | 6.281 | 6.25 | 0.628 | 1.875 | 0.625 | 0.188 | 3.35 | NEMSOK - Object Layer Attributes #1, Kód prvku: SN07.03.0001; Object Layer Attributes #1, Podlaží: 1.NP; Object Layer Attributes #1, Požární odolnost: EI 60; Object Layer Attributes #1, Funkce (venkovní): Ne; Object Layer Attributes #1, Statická funkce: Ne; Object Layer Attributes #1, Vážená stavební neprůzvučnost: 54; Object Layer Attributes #1, Vlhkostní namáhání oboustranné: Ne; Object Layer Attributes #1, Tloušťka opláštění: 2×12,5; Object Layer Attributes #1, Typ SDK desky: vysokopevnostní+bílá; Object Layer Attributes #1, Způsob opláštění: Oboustranné; Object Layer Attributes #1, Tloušťka izolace (2): 50; Object Layer Attributes #1, Objemová hmotnost izolace: 25; Object Layer Attributes #1, Typ profilu pro SDK: CW 50; Object Layer Attributes #1, Rozteč rastru: 625
SDK INSTAL. PŘDSTĚNA VYSOKÁ | Půdorys 1.NP | SDK INSTAL. PŘDSTĚNA VYSOKÁ 0.1 m |  | SDK INSTAL. PŘDSTĚNA VYSOKÁ |  | 1464HWa1096313087 | m3 | Celá stěna | Nový | Suché stavební práce | SDK INSTAL. PŘDSTĚNA VYSOKÁ | no | 1464Stě1096313097 | m3 | Stěna |  | 0.1 | 5.931 | 5.931 | 0.593 | 1.825 | 0.593 | 0.182 | 3.25 | NEMSOK - Object Layer Attributes #1, Kód prvku: SN07.03.0001; Object Layer Attributes #1, Podlaží: 1.NP; Object Layer Attributes #1, Požární odolnost: bez požadavku; Object Layer Attributes #1, Funkce (venkovní): Ne; Object Layer Attributes #1, Statická funkce: Ne; Object Layer Attributes #1, Vlhkostní namáhání oboustranné: Ne; Object Layer Attributes #1, Tloušťka opláštění: 2×12,5; Object Layer Attributes #1, Typ SDK desky: impregnovaná; Object Layer Attributes #1, Způsob opláštění: Jednostranné; Object Layer Attributes #1, Tloušťka izolace (2): 0; Object Layer Attributes #1, Objemová hmotnost izolace: 0; Object Layer Attributes #1, Typ profilu pro SDK: CW 75; Object Layer Attributes #1, Rozteč rastru: 625
SDK INSTAL. PŘDSTĚNA VYSOKÁ | Půdorys 1.NP | SDK INSTAL. PŘDSTĚNA VYSOKÁ 0.1 m |  | SDK INSTAL. PŘDSTĚNA VYSOKÁ |  | 1464HWa1096313088 | m3 | Celá stěna | Nový | Suché stavební práce | SDK INSTAL. PŘDSTĚNA VYSOKÁ | no | 1464Stě1096313102 | m3 | Stěna |  | 0.1 | 5.931 | 5.931 | 0.593 | 1.825 | 0.593 | 0.182 | 3.25 | NEMSOK - Object Layer Attributes #1, Kód prvku: SN07.03.0001; Object Layer Attributes #1, Podlaží: 1.NP; Object Layer Attributes #1, Požární odolnost: bez požadavku; Object Layer Attributes #1, Funkce (venkovní): Ne; Object Layer Attributes #1, Statická funkce: Ne; Object Layer Attributes #1, Vlhkostní namáhání oboustranné: Ne; Object Layer Attributes #1, Tloušťka opláštění: 2×12,5; Object Layer Attributes #1, Typ SDK desky: impregnovaná; Object Layer Attributes #1, Způsob opláštění: Jednostranné; Object Layer Attributes #1, Tloušťka izolace (2): 0; Object Layer Attributes #1, Objemová hmotnost izolace: 0; Object Layer Attributes #1, Typ profilu pro SDK: CW 75; Object Layer Attributes #1, Rozteč rastru: 625
SDK - 1 KCE + DVOJITÉ OPLÁŠTĚNÍ | Půdorys 1.NP | SDK - 1 KCE + DVOJITÉ OPLÁŠTĚNÍ 0.1 m |  | SDK - 1 KCE + DVOJITÉ OPLÁŠTĚNÍ |  | 1464HWa1096313089 | m3 | Celá stěna | Nový | Suché stavební práce | SDK - 1 KCE + DVOJITÉ OPLÁŠTĚNÍ | no | 1464Stě1096313649 | m3 | Stěna |  | 0.1 | 2.931 | 2.899 | 0.293 | 0.875 | 0.29 | 0.088 | 3.35 | NEMSOK - Object Layer Attributes #1, Kód prvku: SN07.03.0001; Object Layer Attributes #1, Podlaží: 1.NP; Object Layer Attributes #1, Požární odolnost: EI 60; Object Layer Attributes #1, Funkce (venkovní): Ne; Object Layer Attributes #1, Statická funkce: Ne; Object Layer Attributes #1, Vážená stavební neprůzvučnost: 54; Object Layer Attributes #1, Vlhkostní namáhání oboustranné: Ne; Object Layer Attributes #1, Tloušťka opláštění: 2×12,5; Object Layer Attributes #1, Typ SDK desky: vysokopevnostní+bílá; Object Layer Attributes #1, Způsob opláštění: Oboustranné; Object Layer Attributes #1, Tloušťka izolace (2): 50; Object Layer Attributes #1, Objemová hmotnost izolace: 25; Object Layer Attributes #1, Typ profilu pro SDK: CW 50; Object Layer Attributes #1, Rozteč rastru: 625
SDK - 2 KCE + DVOJITÉ OPLÁŠTĚNÍ | Půdorys 1.NP | SDK - 2 KCE + DVOJITÉ OPLÁŠTĚNÍ 0.35 m |  | SDK - 2 KCE + DVOJITÉ OPLÁŠTĚNÍ |  | 1464HWa1096313091 | m3 | Celá stěna | Nový | Suché stavební práce | SDK - 2 KCE + DVOJITÉ OPLÁŠTĚNÍ | no | 1464Stě1096313099 | m3 | Stěna |  | 0.35 | 3.35 | 3.35 | 1.173 | 1 | 1.173 | 0.35 | 3.35 | NEMSOK - Object Layer Attributes #1, Kód prvku: SN07.03.0001; Object Layer Attributes #1, Podlaží: 1.NP; Object Layer Attributes #1, Požární odolnost: EI 60; Object Layer Attributes #1, Funkce (venkovní): Ne; Object Layer Attributes #1, Statická funkce: Ne; Object Layer Attributes #1, Vážená stavební neprůzvučnost: 54; Object Layer Attributes #1, Vlhkostní namáhání oboustranné: Ne; Object Layer Attributes #1, Tloušťka opláštění: 2×12,5; Object Layer Attributes #1, Typ SDK desky: vysokopevnostní+bílá; Object Layer Attributes #1, Způsob opláštění: Oboustranné; Object Layer Attributes #1, Tloušťka izolace (2): 100; Object Layer Attributes #1, Objemová hmotnost izolace: 25; Object Layer Attributes #1, Typ profilu pro SDK: 2× CW 100; Object Layer Attributes #1, Rozteč rastru: 625
SDK - 1 KCE + DVOJITÉ OPLÁŠTĚNÍ | Půdorys 1.NP | SDK - 1 KCE + DVOJITÉ OPLÁŠTĚNÍ 0.125 m |  | SDK - 1 KCE + DVOJITÉ OPLÁŠTĚNÍ |  | 1464HWa1096313130 | m3 | Celá stěna | Nový | Suché stavební práce | SDK - 1 KCE + DVOJITÉ OPLÁŠTĚNÍ | no | 1464Stě1096314607 | m3 | Stěna |  | 0.125 | 10.218 | 6.02 | 1.277 | 3.05 | 0.752 | 0.381 | 3.35 | NEMSOK - Object Layer Attributes #1, Kód prvku: SN07.03.0001; Object Layer Attributes #1, Podlaží: 1.NP; Object Layer Attributes #1, Požární odolnost: EI 60; Object Layer Attributes #1, Funkce (venkovní): Ne; Object Layer Attributes #1, Statická funkce: Ne; Object Layer Attributes #1, Vážená stavební neprůzvučnost: 54; Object Layer Attributes #1, Vlhkostní namáhání oboustranné: Ne; Object Layer Attributes #1, Tloušťka opláštění: 2×12,5; Object Layer Attributes #1, Typ SDK desky: vysokopevnostní+bílá; Object Layer Attributes #1, Způsob opláštění: Oboustranné; Object Layer Attributes #1, Tloušťka izolace (2): 75; Object Layer Attributes #1, Objemová hmotnost izolace: 25; Object Layer Attributes #1, Typ profilu pro SDK: CW 75; Object Layer Attributes #1, Rozteč rastru: 625
SDK - 2 KCE + DVOJITÉ OPLÁŠTĚNÍ | Půdorys 1.NP | SDK - 2 KCE + DVOJITÉ OPLÁŠTĚNÍ 0.25 m |  | SDK - 2 KCE + DVOJITÉ OPLÁŠTĚNÍ |  | 1464HWa1096313136 | m3 | Celá stěna | Nový | Suché stavební práce | SDK - 2 KCE + DVOJITÉ OPLÁŠTĚNÍ | no | 1464Stě1096313148 | m3 | Stěna |  | 0.25 | 3.015 | 3.015 | 0.754 | 0.9 | 0.754 | 0.225 | 3.35 | NEMSOK - Object Layer Attributes #1, Kód prvku: SN07.03.0001; Object Layer Attributes #1, Podlaží: 1.NP; Object Layer Attributes #1, Požární odolnost: EI 60; Object Layer Attributes #1, Funkce (venkovní): Ne; Object Layer Attributes #1, Statická funkce: Ne; Object Layer Attributes #1, Vážená stavební neprůzvučnost: 54; Object Layer Attributes #1, Vlhkostní namáhání oboustranné: Ne; Object Layer Attributes #1, Tloušťka opláštění: 2×12,5; Object Layer Attributes #1, Typ SDK desky: vysokopevnostní+bílá; Object Layer Attributes #1, Způsob opláštění: Oboustranné; Object Layer Attributes #1, Tloušťka izolace (2): 100; Object Layer Attributes #1, Objemová hmotnost izolace: 25; Object Layer Attributes #1, Typ profilu pro SDK: 2× CW 100; Object Layer Attributes #1, Rozteč rastru: 625
SDK OPL. PROFESÍ/SDK OPL. BEZ PO | Půdorys 1.NP | SDK OPL. PROFESÍ/SDK OPL. BEZ PO 0.075 m |  | SDK OPL. PROFESÍ/SDK OPL. BEZ PO |  | 1464HWa1096313149 | m3 | Celá stěna | Nový | Suché stavební práce | SDK OPL. PROFESÍ/SDK OPL. BEZ PO | no | 1464Stě1096313166 | m3 | Stěna |  | 0.075 | 3.169 | 3.169 | 0.238 | 0.975 | 0.238 | 0.073 | 3.25 | NEMSOK - Object Layer Attributes #1, Kód prvku: SN07.03.0001; Object Layer Attributes #1, Podlaží: 1.NP; Object Layer Attributes #1, Požární odolnost: bez požadavku; Object Layer Attributes #1, Funkce (venkovní): Ne; Object Layer Attributes #1, Statická funkce: Ne; Object Layer Attributes #1, Vlhkostní namáhání oboustranné: Ne; Object Layer Attributes #1, Tloušťka opláštění: 2×12,5; Object Layer Attributes #1, Typ SDK desky: vysokopevnostní+bílá; Object Layer Attributes #1, Způsob opláštění: Jednostranné; Object Layer Attributes #1, Tloušťka izolace (2): 0; Object Layer Attributes #1, Objemová hmotnost izolace: 0; Object Layer Attributes #1, Typ profilu pro SDK: CW 100; Object Layer Attributes #1, Rozteč rastru: 625
SDK INSTAL. PŘDSTĚNA VYSOKÁ | Půdorys 1.NP | SDK INSTAL. PŘDSTĚNA VYSOKÁ 0.2 m |  | SDK INSTAL. PŘDSTĚNA VYSOKÁ |  | 1464HWa1096313150 | m3 | Celá stěna | Nový | Suché stavební práce | SDK INSTAL. PŘDSTĚNA VYSOKÁ | no | 1464Stě1096313160 | m3 | Stěna |  | 0.2 | 3.169 | 3.169 | 0.634 | 0.975 | 0.634 | 0.195 | 3.25 | NEMSOK - Object Layer Attributes #1, Kód prvku: SN07.03.0001; Object Layer Attributes #1, Podlaží: 1.NP; Object Layer Attributes #1, Požární odolnost: bez požadavku; Object Layer Attributes #1, Funkce (venkovní): Ne; Object Layer Attributes #1, Statická funkce: Ne; Object Layer Attributes #1, Vlhkostní namáhání oboustranné: Ne; Object Layer Attributes #1, Tloušťka opláštění: 2×12,5; Object Layer Attributes #1, Typ SDK desky: impregnovaná; Object Layer Attributes #1, Způsob opláštění: Jednostranné; Object Layer Attributes #1, Tloušťka izolace (2): 0; Object Layer Attributes #1, Objemová hmotnost izolace: 0; Object Layer Attributes #1, Typ profilu pro SDK: CW 100; Object Layer Attributes #1, Rozteč rastru: 625
SDK - 1 KCE + DVOJITÉ OPLÁŠTĚNÍ | Půdorys 1.NP | SDK - 1 KCE + DVOJITÉ OPLÁŠTĚNÍ 0.125 m |  | SDK - 1 KCE + DVOJITÉ OPLÁŠTĚNÍ |  | 1464HWa1096313153 | m3 | Celá stěna | Nový | Suché stavební práce | SDK - 1 KCE + DVOJITÉ OPLÁŠTĚNÍ | no | 1464Stě1096314497 | m3 | Stěna |  | 0.125 | 7.705 | 4.056 | 0.963 | 2.3 | 0.507 | 0.287 | 3.35 | NEMSOK - Object Layer Attributes #1, Kód prvku: SN07.03.0001; Object Layer Attributes #1, Podlaží: 1.NP; Object Layer Attributes #1, Požární odolnost: EI 60; Object Layer Attributes #1, Funkce (venkovní): Ne; Object Layer Attributes #1, Statická funkce: Ne; Object Layer Attributes #1, Vážená stavební neprůzvučnost: 54; Object Layer Attributes #1, Vlhkostní namáhání oboustranné: Ne; Object Layer Attributes #1, Tloušťka opláštění: 2×12,5; Object Layer Attributes #1, Typ SDK desky: vysokopevnostní+bílá; Object Layer Attributes #1, Způsob opláštění: Oboustranné; Object Layer Attributes #1, Tloušťka izolace (2): 75; Object Layer Attributes #1, Objemová hmotnost izolace: 25; Object Layer Attributes #1, Typ profilu pro SDK: CW 75; Object Layer Attributes #1, Rozteč rastru: 625
SDK INSTAL. PŘDSTĚNA VYSOKÁ | Půdorys 1.NP | SDK INSTAL. PŘDSTĚNA VYSOKÁ 0.15 m |  | SDK INSTAL. PŘDSTĚNA VYSOKÁ |  | 1464HWa1096313161 | m3 | Celá stěna | Nový | Suché stavební práce | SDK INSTAL. PŘDSTĚNA VYSOKÁ | no | 1464Stě1096314699 | m3 | Stěna |  | 0.15 | 5.688 | 5.592 | 0.853 | 1.75 | 0.839 | 0.262 | 3.25 | NEMSOK - Object Layer Attributes #1, Kód prvku: SN07.03.0001; Object Layer Attributes #1, Podlaží: 1.NP; Object Layer Attributes #1, Požární odolnost: bez požadavku; Object Layer Attributes #1, Funkce (venkovní): Ne; Object Layer Attributes #1, Statická funkce: Ne; Object Layer Attributes #1, Vlhkostní namáhání oboustranné: Ne; Object Layer Attributes #1, Tloušťka opláštění: 2×12,5; Object Layer Attributes #1, Typ SDK desky: impregnovaná; Object Layer Attributes #1, Způsob opláštění: Jednostranné; Object Layer Attributes #1, Tloušťka izolace (2): 0; Object Layer Attributes #1, Objemová hmotnost izolace: 0; Object Layer Attributes #1, Typ profilu pro SDK: CW 100; Object Layer Attributes #1, Rozteč rastru: 625
SDK INSTAL. PŘDSTĚNA VYSOKÁ | Půdorys 1.NP | SDK INSTAL. PŘDSTĚNA VYSOKÁ 0.15 m |  | SDK INSTAL. PŘDSTĚNA VYSOKÁ |  | 1464HWa1096313162 | m3 | Celá stěna | Nový | Suché stavební práce | SDK INSTAL. PŘDSTĚNA VYSOKÁ | no | 1464Stě1096314484 | m3 | Stěna |  | 0.15 | 5.444 | 5.444 | 0.817 | 1.675 | 0.817 | 0.251 | 3.25 | NEMSOK - Object Layer Attributes #1, Kód prvku: SN07.03.0001; Object Layer Attributes #1, Podlaží: 1.NP; Object Layer Attributes #1, Požární odolnost: bez požadavku; Object Layer Attributes #1, Funkce (venkovní): Ne; Object Layer Attributes #1, Statická funkce: Ne; Object Layer Attributes #1, Vlhkostní namáhání oboustranné: Ne; Object Layer Attributes #1, Tloušťka opláštění: 2×12,5; Object Layer Attributes #1, Typ SDK desky: impregnovaná; Object Layer Attributes #1, Způsob opláštění: Jednostranné; Object Layer Attributes #1, Tloušťka izolace (2): 0; Object Layer Attributes #1, Objemová hmotnost izolace: 0; Object Layer Attributes #1, Typ profilu pro SDK: CW 100; Object Layer Attributes #1, Rozteč rastru: 625
SDK - 1 KCE + DVOJITÉ OPLÁŠTĚNÍ | Půdorys 1.NP | SDK - 1 KCE + DVOJITÉ OPLÁŠTĚNÍ 0.1 m |  | SDK - 1 KCE + DVOJITÉ OPLÁŠTĚNÍ |  | 1464HWa1096313178 | m3 | Celá stěna | Nový | Suché stavební práce | SDK - 1 KCE + DVOJITÉ OPLÁŠTĚNÍ | no | 1464Stě1096314474 | m3 | Stěna |  | 0.1 | 2.345 | 2.296 | 0.234 | 0.7 | 0.23 | 0.07 | 3.35 | NEMSOK - Object Layer Attributes #1, Kód prvku: SN07.03.0001; Object Layer Attributes #1, Podlaží: 1.NP; Object Layer Attributes #1, Požární odolnost: EI 60; Object Layer Attributes #1, Funkce (venkovní): Ne; Object Layer Attributes #1, Statická funkce: Ne; Object Layer Attributes #1, Vážená stavební neprůzvučnost: 54; Object Layer Attributes #1, Vlhkostní namáhání oboustranné: Ne; Object Layer Attributes #1, Tloušťka opláštění: 2×12,5; Object Layer Attributes #1, Typ SDK desky: vysokopevnostní+bílá; Object Layer Attributes #1, Způsob opláštění: Oboustranné; Object Layer Attributes #1, Tloušťka izolace (2): 50; Object Layer Attributes #1, Objemová hmotnost izolace: 25; Object Layer Attributes #1, Typ profilu pro SDK: CW 50; Object Layer Attributes #1, Rozteč rastru: 625
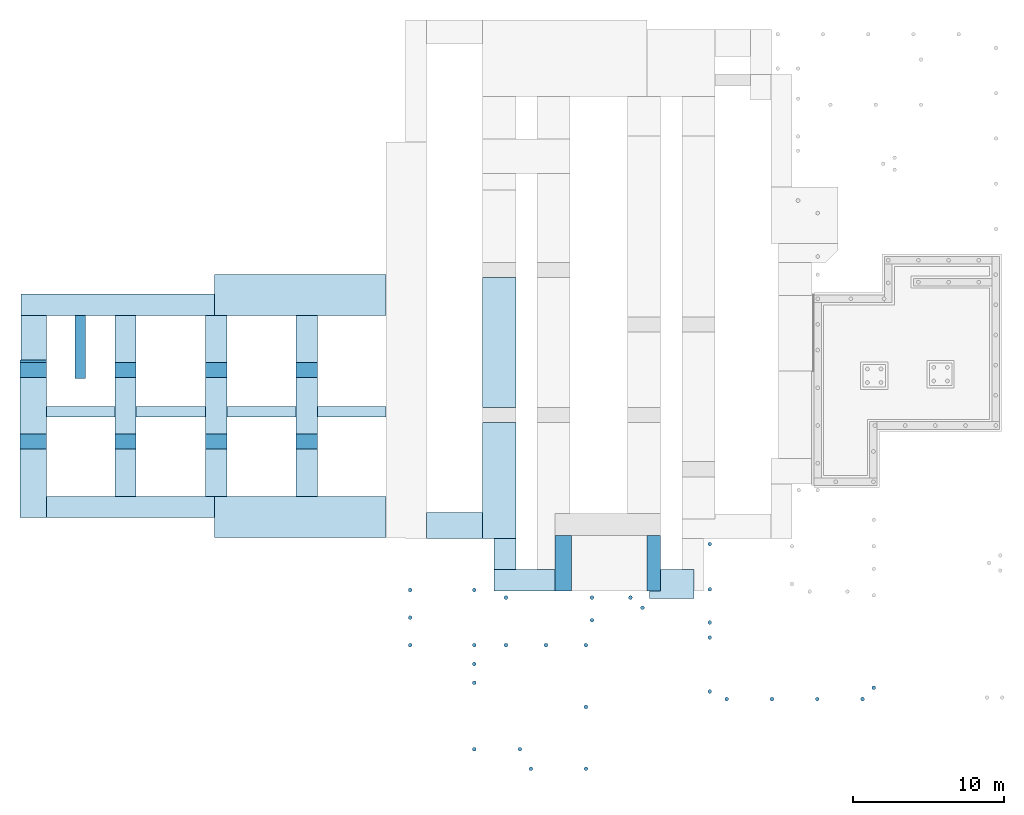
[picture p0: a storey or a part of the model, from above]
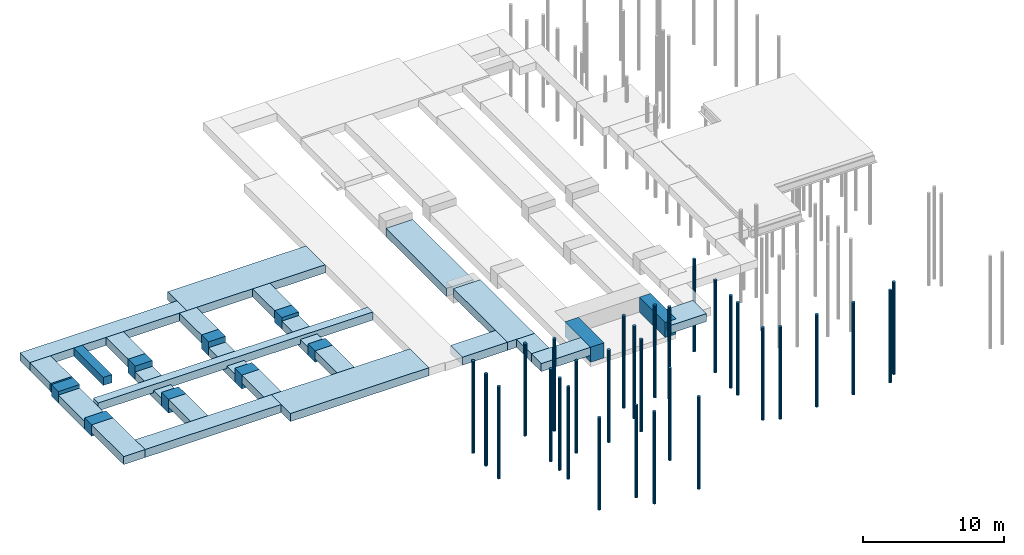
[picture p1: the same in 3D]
Properties of the parts of a building model (IFC4), part 36 of 45

# IfcWall (2385)
Name | In | Material | Faktor | Označení | Požární odolnost | Allright_Stavebni_dil_ID | Jednotka | Název_objektu | Object Layer Attributes #1, Status | Object Layer Attributes #1, Práce | Object Layer Attributes #1, Materiál | Object Layer Attributes #1, Staticky nosná konstrukce | Object Layer Attributes #1, Allright_Stavebni_dil_ID | Object Layer Attributes #1, Jednotka | Object Layer Attributes #1, Název_objektu | ThermalTransmittance (W/K/m2) | Width (m) | GrossSideArea (m2) | NetSideArea (m2) | GrossVolume (m3) | Length (m) | NetVolume (m3) | GrossFootprintArea (m2) | Height (m)
SDK INSTAL. PŘDSTĚNA VYSOKÁ | Půdorys 1.NP | SDK INSTAL. PŘDSTĚNA VYSOKÁ 0.1 m |  | SDK INSTAL. PŘDSTĚNA VYSOKÁ |  | 1464HWa1096313231 | m3 | Celá stěna | Nový | Suché stavební práce | SDK INSTAL. PŘDSTĚNA VYSOKÁ | no | 1464Stě1096313970 | m3 | Stěna |  | 0.1 | 3.25 | 3.169 | 0.325 | 1 | 0.317 | 0.1 | 3.25 | NEMSOK - Object Layer Attributes #1, Kód prvku: SN07.03.0001; Object Layer Attributes #1, Podlaží: 1.NP; Object Layer Attributes #1, Požární odolnost: bez požadavku; Object Layer Attributes #1, Funkce (venkovní): Ne; Object Layer Attributes #1, Statická funkce: Ne; Object Layer Attributes #1, Vlhkostní namáhání oboustranné: Ne; Object Layer Attributes #1, Tloušťka opláštění: 2×12,5; Object Layer Attributes #1, Typ SDK desky: impregnovaná; Object Layer Attributes #1, Způsob opláštění: Jednostranné; Object Layer Attributes #1, Tloušťka izolace (2): 0; Object Layer Attributes #1, Objemová hmotnost izolace: 0; Object Layer Attributes #1, Typ profilu pro SDK: CW 75; Object Layer Attributes #1, Rozteč rastru: 625
SDK - 1 KCE + DVOJITÉ OPLÁŠTĚNÍ | Půdorys 1.NP | SDK - 1 KCE + DVOJITÉ OPLÁŠTĚNÍ 0.125 m |  | SDK - 1 KCE + DVOJITÉ OPLÁŠTĚNÍ |  | 1464HWa1096313233 | m3 | Celá stěna | Nový | Suché stavební práce | SDK - 1 KCE + DVOJITÉ OPLÁŠTĚNÍ | no | 1464Stě1096313767 | m3 | Stěna |  | 0.125 | 9.799 | 9.659 | 1.225 | 2.925 | 1.207 | 0.366 | 3.35 | NEMSOK - Object Layer Attributes #1, Kód prvku: SN07.03.0001; Object Layer Attributes #1, Podlaží: 1.NP; Object Layer Attributes #1, Požární odolnost: EI 60; Object Layer Attributes #1, Funkce (venkovní): Ne; Object Layer Attributes #1, Statická funkce: Ne; Object Layer Attributes #1, Vážená stavební neprůzvučnost: 54; Object Layer Attributes #1, Vlhkostní namáhání oboustranné: Ne; Object Layer Attributes #1, Tloušťka opláštění: 2×12,5; Object Layer Attributes #1, Typ SDK desky: vysokopevnostní+bílá; Object Layer Attributes #1, Způsob opláštění: Oboustranné; Object Layer Attributes #1, Tloušťka izolace (2): 75; Object Layer Attributes #1, Objemová hmotnost izolace: 25; Object Layer Attributes #1, Typ profilu pro SDK: CW 75; Object Layer Attributes #1, Rozteč rastru: 625
SDK - 1 KCE + DVOJITÉ OPLÁŠTĚNÍ | Půdorys 1.NP | SDK - 1 KCE + DVOJITÉ OPLÁŠTĚNÍ 0.125 m |  | SDK - 1 KCE + DVOJITÉ OPLÁŠTĚNÍ |  | 1464HWa1096313248 | m3 | Celá stěna | Nový | Suché stavební práce | SDK - 1 KCE + DVOJITÉ OPLÁŠTĚNÍ | no | 1464Stě1096313301 | m3 | Stěna |  | 0.125 | 1.675 | 1.675 | 0.209 | 0.5 | 0.209 | 0.062 | 3.35 | NEMSOK - Object Layer Attributes #1, Kód prvku: SN07.03.0001; Object Layer Attributes #1, Podlaží: 1.NP; Object Layer Attributes #1, Požární odolnost: EI 60; Object Layer Attributes #1, Funkce (venkovní): Ne; Object Layer Attributes #1, Statická funkce: Ne; Object Layer Attributes #1, Vážená stavební neprůzvučnost: 54; Object Layer Attributes #1, Vlhkostní namáhání oboustranné: Ne; Object Layer Attributes #1, Tloušťka opláštění: 2×12,5; Object Layer Attributes #1, Typ SDK desky: vysokopevnostní+bílá; Object Layer Attributes #1, Způsob opláštění: Oboustranné; Object Layer Attributes #1, Tloušťka izolace (2): 75; Object Layer Attributes #1, Objemová hmotnost izolace: 25; Object Layer Attributes #1, Typ profilu pro SDK: CW 75; Object Layer Attributes #1, Rozteč rastru: 625
SDK INSTAL. PŘDSTĚNA VYSOKÁ | Půdorys 1.NP | SDK INSTAL. PŘDSTĚNA VYSOKÁ 0.1 m |  | SDK INSTAL. PŘDSTĚNA VYSOKÁ |  | 1464HWa1096313250 | m3 | Celá stěna | Nový | Suché stavební práce | SDK INSTAL. PŘDSTĚNA VYSOKÁ | no | 1464Stě1096313299 | m3 | Stěna |  | 0.1 | 3.006 | 3.006 | 0.301 | 0.925 | 0.301 | 0.093 | 3.25 | NEMSOK - Object Layer Attributes #1, Kód prvku: SN07.03.0001; Object Layer Attributes #1, Podlaží: 1.NP; Object Layer Attributes #1, Požární odolnost: bez požadavku; Object Layer Attributes #1, Funkce (venkovní): Ne; Object Layer Attributes #1, Statická funkce: Ne; Object Layer Attributes #1, Vlhkostní namáhání oboustranné: Ne; Object Layer Attributes #1, Tloušťka opláštění: 2×12,5; Object Layer Attributes #1, Typ SDK desky: impregnovaná; Object Layer Attributes #1, Způsob opláštění: Jednostranné; Object Layer Attributes #1, Tloušťka izolace (2): 0; Object Layer Attributes #1, Objemová hmotnost izolace: 0; Object Layer Attributes #1, Typ profilu pro SDK: CW 75; Object Layer Attributes #1, Rozteč rastru: 625
SDK OPL. PROFESÍ/SDK OPL. BEZ PO | Půdorys 1.NP | SDK OPL. PROFESÍ/SDK OPL. BEZ PO 0.1 m |  | SDK OPL. PROFESÍ/SDK OPL. BEZ PO |  | 1464HWa1096313284 | m3 | Celá stěna | Nový | Suché stavební práce | SDK OPL. PROFESÍ/SDK OPL. BEZ PO | no | 1464Stě1096313287 | m3 | Stěna |  | 0.1 | 2.762 | 2.763 | 0.276 | 0.85 | 0.276 | 0.085 | 3.25 | NEMSOK - Object Layer Attributes #1, Kód prvku: SN07.03.0001; Object Layer Attributes #1, Podlaží: 1.NP; Object Layer Attributes #1, Požární odolnost: bez požadavku; Object Layer Attributes #1, Funkce (venkovní): Ne; Object Layer Attributes #1, Statická funkce: Ne; Object Layer Attributes #1, Vlhkostní namáhání oboustranné: Ne; Object Layer Attributes #1, Tloušťka opláštění: 2×12,5; Object Layer Attributes #1, Typ SDK desky: vysokopevnostní+bílá; Object Layer Attributes #1, Způsob opláštění: Jednostranné; Object Layer Attributes #1, Tloušťka izolace (2): 0; Object Layer Attributes #1, Objemová hmotnost izolace: 0; Object Layer Attributes #1, Typ profilu pro SDK: CW 75; Object Layer Attributes #1, Rozteč rastru: 625
SDK - 1 KCE + DVOJITÉ OPLÁŠTĚNÍ | Půdorys 1.NP | SDK - 1 KCE + DVOJITÉ OPLÁŠTĚNÍ 0.125 m |  | SDK - 1 KCE + DVOJITÉ OPLÁŠTĚNÍ |  | 1464HWa1096313288 | m3 | Celá stěna | Nový | Suché stavební práce | SDK - 1 KCE + DVOJITÉ OPLÁŠTĚNÍ | no | 1464Stě1096314218 | m3 | Stěna |  | 0.125 | 8.476 | 8.228 | 1.059 | 2.53 | 1.028 | 0.316 | 3.35 | NEMSOK - Object Layer Attributes #1, Kód prvku: SN07.03.0001; Object Layer Attributes #1, Podlaží: 1.NP; Object Layer Attributes #1, Požární odolnost: EI 60; Object Layer Attributes #1, Funkce (venkovní): Ne; Object Layer Attributes #1, Statická funkce: Ne; Object Layer Attributes #1, Vážená stavební neprůzvučnost: 54; Object Layer Attributes #1, Vlhkostní namáhání oboustranné: Ne; Object Layer Attributes #1, Tloušťka opláštění: 2×12,5; Object Layer Attributes #1, Typ SDK desky: vysokopevnostní+bílá; Object Layer Attributes #1, Způsob opláštění: Oboustranné; Object Layer Attributes #1, Tloušťka izolace (2): 75; Object Layer Attributes #1, Objemová hmotnost izolace: 25; Object Layer Attributes #1, Typ profilu pro SDK: CW 75; Object Layer Attributes #1, Rozteč rastru: 625
SDK - 1 KCE + DVOJITÉ OPLÁŠTĚNÍ | Půdorys 1.NP | SDK - 1 KCE + DVOJITÉ OPLÁŠTĚNÍ 0.125 m |  | SDK - 1 KCE + DVOJITÉ OPLÁŠTĚNÍ |  | 1464HWa1096313290 | m3 | Celá stěna | Nový | Suché stavební práce | SDK - 1 KCE + DVOJITÉ OPLÁŠTĚNÍ | no | 1464Stě1096314026 | m3 | Stěna |  | 0.125 | 7.119 | 3.905 | 0.89 | 2.125 | 0.488 | 0.266 | 3.35 | NEMSOK - Object Layer Attributes #1, Kód prvku: SN07.03.0001; Object Layer Attributes #1, Podlaží: 1.NP; Object Layer Attributes #1, Požární odolnost: EI 60; Object Layer Attributes #1, Funkce (venkovní): Ne; Object Layer Attributes #1, Statická funkce: Ne; Object Layer Attributes #1, Vážená stavební neprůzvučnost: 54; Object Layer Attributes #1, Vlhkostní namáhání oboustranné: Ne; Object Layer Attributes #1, Tloušťka opláštění: 2×12,5; Object Layer Attributes #1, Typ SDK desky: vysokopevnostní+bílá; Object Layer Attributes #1, Způsob opláštění: Oboustranné; Object Layer Attributes #1, Tloušťka izolace (2): 75; Object Layer Attributes #1, Objemová hmotnost izolace: 25; Object Layer Attributes #1, Typ profilu pro SDK: CW 75; Object Layer Attributes #1, Rozteč rastru: 625
SDK - 1 KCE + DVOJITÉ OPLÁŠTĚNÍ | Půdorys 1.NP | SDK - 1 KCE + DVOJITÉ OPLÁŠTĚNÍ 0.125 m |  | SDK - 1 KCE + DVOJITÉ OPLÁŠTĚNÍ |  | 1464HWa1096313292 | m3 | Celá stěna | Nový | Suché stavební práce | SDK - 1 KCE + DVOJITÉ OPLÁŠTĚNÍ | no | 1464Stě1096313967 | m3 | Stěna |  | 0.125 | 7.035 | 3.737 | 0.879 | 2.1 | 0.478 | 0.262 | 3.35 | NEMSOK - Object Layer Attributes #1, Kód prvku: SN07.03.0001; Object Layer Attributes #1, Podlaží: 1.NP; Object Layer Attributes #1, Požární odolnost: EI 60; Object Layer Attributes #1, Funkce (venkovní): Ne; Object Layer Attributes #1, Statická funkce: Ne; Object Layer Attributes #1, Vážená stavební neprůzvučnost: 54; Object Layer Attributes #1, Vlhkostní namáhání oboustranné: Ne; Object Layer Attributes #1, Tloušťka opláštění: 2×12,5; Object Layer Attributes #1, Typ SDK desky: vysokopevnostní+bílá; Object Layer Attributes #1, Způsob opláštění: Oboustranné; Object Layer Attributes #1, Tloušťka izolace (2): 75; Object Layer Attributes #1, Objemová hmotnost izolace: 25; Object Layer Attributes #1, Typ profilu pro SDK: CW 75; Object Layer Attributes #1, Rozteč rastru: 625
SDK OPL. PROFESÍ/SDK OPL. BEZ PO | Půdorys 1.NP | SDK OPL. PROFESÍ/SDK OPL. BEZ PO 0.1 m |  | SDK OPL. PROFESÍ/SDK OPL. BEZ PO |  | 1464HWa1096313433 | m3 | Celá stěna | Nový | Suché stavební práce | SDK OPL. PROFESÍ/SDK OPL. BEZ PO | no | 1464Stě1096314300 | m3 | Stěna |  | 0.1 | 5.444 | 5.224 | 0.544 | 1.675 | 0.522 | 0.168 | 3.25 | NEMSOK - Object Layer Attributes #1, Kód prvku: SN07.03.0001; Object Layer Attributes #1, Podlaží: 1.NP; Object Layer Attributes #1, Požární odolnost: bez požadavku; Object Layer Attributes #1, Funkce (venkovní): Ne; Object Layer Attributes #1, Statická funkce: Ne; Object Layer Attributes #1, Vlhkostní namáhání oboustranné: Ne; Object Layer Attributes #1, Tloušťka opláštění: 2×12,5; Object Layer Attributes #1, Typ SDK desky: vysokopevnostní+bílá; Object Layer Attributes #1, Způsob opláštění: Jednostranné; Object Layer Attributes #1, Tloušťka izolace (2): 0; Object Layer Attributes #1, Objemová hmotnost izolace: 0; Object Layer Attributes #1, Typ profilu pro SDK: CW 75; Object Layer Attributes #1, Rozteč rastru: 625
SDK OPL. PROFESÍ/SDK OPL. BEZ PO | Půdorys 1.NP | SDK OPL. PROFESÍ/SDK OPL. BEZ PO 0.1 m |  | SDK OPL. PROFESÍ/SDK OPL. BEZ PO |  | 1464HWa1096313434 | m3 | Celá stěna | Nový | Suché stavební práce | SDK OPL. PROFESÍ/SDK OPL. BEZ PO | no | 1464Stě1096313439 | m3 | Stěna |  | 0.1 | 0.65 | 0.65 | 0.065 | 0.2 | 0.065 | 0.02 | 3.25 | NEMSOK - Object Layer Attributes #1, Kód prvku: SN07.03.0001; Object Layer Attributes #1, Podlaží: 1.NP; Object Layer Attributes #1, Požární odolnost: bez požadavku; Object Layer Attributes #1, Funkce (venkovní): Ne; Object Layer Attributes #1, Statická funkce: Ne; Object Layer Attributes #1, Vlhkostní namáhání oboustranné: Ne; Object Layer Attributes #1, Tloušťka opláštění: 2×12,5; Object Layer Attributes #1, Typ SDK desky: vysokopevnostní+bílá; Object Layer Attributes #1, Způsob opláštění: Jednostranné; Object Layer Attributes #1, Tloušťka izolace (2): 0; Object Layer Attributes #1, Objemová hmotnost izolace: 0; Object Layer Attributes #1, Typ profilu pro SDK: CW 75; Object Layer Attributes #1, Rozteč rastru: 625
SDK INSTAL. PŘDSTĚNA VYSOKÁ | Půdorys 1.NP | SDK INSTAL. PŘDSTĚNA VYSOKÁ 0.15 m |  | SDK INSTAL. PŘDSTĚNA VYSOKÁ |  | 1464HWa1096313440 | m3 | Celá stěna | Nový | Suché stavební práce | SDK INSTAL. PŘDSTĚNA VYSOKÁ | no | 1464Stě1096314684 | m3 | Stěna |  | 0.15 | 19.988 | 15.698 | 2.998 | 6.15 | 2.353 | 0.923 | 3.25 | NEMSOK - Object Layer Attributes #1, Kód prvku: SN07.03.0001; Object Layer Attributes #1, Podlaží: 1.NP; Object Layer Attributes #1, Požární odolnost: bez požadavku; Object Layer Attributes #1, Funkce (venkovní): Ne; Object Layer Attributes #1, Statická funkce: Ne; Object Layer Attributes #1, Vlhkostní namáhání oboustranné: Ne; Object Layer Attributes #1, Tloušťka opláštění: 2×12,5; Object Layer Attributes #1, Typ SDK desky: impregnovaná; Object Layer Attributes #1, Způsob opláštění: Jednostranné; Object Layer Attributes #1, Tloušťka izolace (2): 0; Object Layer Attributes #1, Objemová hmotnost izolace: 0; Object Layer Attributes #1, Typ profilu pro SDK: CW 100; Object Layer Attributes #1, Rozteč rastru: 625
SDK - 1 KCE + DVOJITÉ OPLÁŠTĚNÍ | Půdorys 1.NP | SDK - 1 KCE + DVOJITÉ OPLÁŠTĚNÍ 0.125 m |  | SDK - 1 KCE + DVOJITÉ OPLÁŠTĚNÍ |  | 1464HWa1096313461 | m3 | Celá stěna | Nový | Suché stavební práce | SDK - 1 KCE + DVOJITÉ OPLÁŠTĚNÍ | no | 1464Stě1096313886 | m3 | Stěna |  | 0.125 | 25.041 | 22.756 | 3.13 | 7.475 | 2.845 | 0.934 | 3.35 | NEMSOK - Object Layer Attributes #1, Kód prvku: SN07.03.0001; Object Layer Attributes #1, Podlaží: 1.NP; Object Layer Attributes #1, Požární odolnost: EI 60; Object Layer Attributes #1, Funkce (venkovní): Ne; Object Layer Attributes #1, Statická funkce: Ne; Object Layer Attributes #1, Vážená stavební neprůzvučnost: 54; Object Layer Attributes #1, Vlhkostní namáhání oboustranné: Ne; Object Layer Attributes #1, Tloušťka opláštění: 2×12,5; Object Layer Attributes #1, Typ SDK desky: vysokopevnostní+bílá; Object Layer Attributes #1, Způsob opláštění: Oboustranné; Object Layer Attributes #1, Tloušťka izolace (2): 75; Object Layer Attributes #1, Objemová hmotnost izolace: 25; Object Layer Attributes #1, Typ profilu pro SDK: CW 75; Object Layer Attributes #1, Rozteč rastru: 625
SDK OPL. PROFESÍ/SDK OPL. BEZ PO | Půdorys 1.NP | SDK OPL. PROFESÍ/SDK OPL. BEZ PO 0.075 m |  | SDK OPL. PROFESÍ/SDK OPL. BEZ PO |  | 1464HWa1096313552 | m3 | Celá stěna | Nový | Suché stavební práce | SDK OPL. PROFESÍ/SDK OPL. BEZ PO | no | 1464Stě1096313555 | m3 | Stěna |  | 0.075 | 0.65 | 0.65 | 0.049 | 0.2 | 0.049 | 0.015 | 3.25 | NEMSOK - Object Layer Attributes #1, Kód prvku: SN07.03.0001; Object Layer Attributes #1, Podlaží: 1.NP; Object Layer Attributes #1, Požární odolnost: bez požadavku; Object Layer Attributes #1, Funkce (venkovní): Ne; Object Layer Attributes #1, Statická funkce: Ne; Object Layer Attributes #1, Vlhkostní namáhání oboustranné: Ne; Object Layer Attributes #1, Tloušťka opláštění: 2×12,5; Object Layer Attributes #1, Typ SDK desky: vysokopevnostní+bílá; Object Layer Attributes #1, Způsob opláštění: Jednostranné; Object Layer Attributes #1, Tloušťka izolace (2): 0; Object Layer Attributes #1, Objemová hmotnost izolace: 0; Object Layer Attributes #1, Typ profilu pro SDK: CW 100; Object Layer Attributes #1, Rozteč rastru: 625
SDK - 1 KCE + DVOJITÉ OPLÁŠTĚNÍ | Půdorys 1.NP | SDK - 1 KCE + DVOJITÉ OPLÁŠTĚNÍ 0.125 m |  | SDK - 1 KCE + DVOJITÉ OPLÁŠTĚNÍ |  | 1464HWa1096313980 | m3 | Celá stěna | Nový | Suché stavební práce | SDK - 1 KCE + DVOJITÉ OPLÁŠTĚNÍ | no | 1464Stě1096313987 | m3 | Stěna |  | 0.125 | 1.818 | 0 | 0.227 | 0.9 | 0 | 0.112 | 2.02 | NEMSOK - Object Layer Attributes #1, Kód prvku: SN07.03.0001; Object Layer Attributes #1, Podlaží: 1.NP; Object Layer Attributes #1, Požární odolnost: EI 60; Object Layer Attributes #1, Funkce (venkovní): Ne; Object Layer Attributes #1, Statická funkce: Ne; Object Layer Attributes #1, Vážená stavební neprůzvučnost: 54; Object Layer Attributes #1, Vlhkostní namáhání oboustranné: Ne; Object Layer Attributes #1, Tloušťka opláštění: 2×12,5; Object Layer Attributes #1, Typ SDK desky: vysokopevnostní+bílá; Object Layer Attributes #1, Způsob opláštění: Oboustranné; Object Layer Attributes #1, Tloušťka izolace (2): 75; Object Layer Attributes #1, Objemová hmotnost izolace: 25; Object Layer Attributes #1, Typ profilu pro SDK: CW 75; Object Layer Attributes #1, Rozteč rastru: 625
SDK - 1 KCE + DVOJITÉ OPLÁŠTĚNÍ | Půdorys 1.NP | SDK - 1 KCE + DVOJITÉ OPLÁŠTĚNÍ 0.2 m |  | SDK - 1 KCE + DVOJITÉ OPLÁŠTĚNÍ |  | 1464HWa1096314463 | m3 | Celá stěna | Nový | Suché stavební práce | SDK - 1 KCE + DVOJITÉ OPLÁŠTĚNÍ | no | 1464Stě1096314471 | m3 | Stěna |  | 0.2 | 1.524 | 1.524 | 0.305 | 0.455 | 0.305 | 0.091 | 3.35 | NEMSOK - Object Layer Attributes #1, Kód prvku: SN07.03.0001; Object Layer Attributes #1, Podlaží: 1.NP; Object Layer Attributes #1, Požární odolnost: EI 60; Object Layer Attributes #1, Funkce (venkovní): Ne; Object Layer Attributes #1, Statická funkce: Ne; Object Layer Attributes #1, Vážená stavební neprůzvučnost: 54; Object Layer Attributes #1, Vlhkostní namáhání oboustranné: Ne; Object Layer Attributes #1, Tloušťka opláštění: 2×12,5; Object Layer Attributes #1, Typ SDK desky: vysokopevnostní+bílá; Object Layer Attributes #1, Způsob opláštění: Oboustranné; Object Layer Attributes #1, Tloušťka izolace (2): 150; Object Layer Attributes #1, Objemová hmotnost izolace: 25; Object Layer Attributes #1, Typ profilu pro SDK: CW 150; Object Layer Attributes #1, Rozteč rastru: 625
SDK OPL. PROFESÍ/SDK OPL. BEZ PO | Půdorys 1.NP | SDK OPL. PROFESÍ/SDK OPL. BEZ PO 0.075 m |  | SDK OPL. PROFESÍ/SDK OPL. BEZ PO |  | 1464HWa1096313550 | m3 | Celá stěna | Nový | Suché stavební práce | SDK OPL. PROFESÍ/SDK OPL. BEZ PO | no | 1464Stě1096313557 | m3 | Stěna |  | 0.075 | 1.316 | 1.316 | 0.099 | 0.405 | 0.099 | 0.03 | 3.25 | NEMSOK - Object Layer Attributes #1, Kód prvku: SN07.03.0001; Object Layer Attributes #1, Podlaží: 1.NP; Object Layer Attributes #1, Požární odolnost: bez požadavku; Object Layer Attributes #1, Funkce (venkovní): Ne; Object Layer Attributes #1, Statická funkce: Ne; Object Layer Attributes #1, Vlhkostní namáhání oboustranné: Ne; Object Layer Attributes #1, Tloušťka opláštění: 2×12,5; Object Layer Attributes #1, Typ SDK desky: vysokopevnostní+bílá; Object Layer Attributes #1, Způsob opláštění: Jednostranné; Object Layer Attributes #1, Tloušťka izolace (2): 0; Object Layer Attributes #1, Objemová hmotnost izolace: 0; Object Layer Attributes #1, Typ profilu pro SDK: CW 100; Object Layer Attributes #1, Rozteč rastru: 625
SDK ŠACHTOVÁ STĚNA/SDK OPL. S PO | Půdorys 1.NP | SDK ŠACHTOVÁ STĚNA/SDK OPL. S PO 0.075 m |  | SDK ŠACHTOVÁ STĚNA/SDK OPL. S PO |  | 1464HWa1096312767 | m3 | Celá stěna | Nový | Suché stavební práce | SDK ŠACHTOVÁ STĚNA/SDK OPL. S PO | no | 1464Stě1096312790 | m3 | Stěna |  | 0.075 | 0.821 | 0.821 | 0.062 | 0.245 | 0.062 | 0.018 | 3.35 | NEMSOK - Object Layer Attributes #1, Kód prvku: SN07.03.0001; Object Layer Attributes #1, Podlaží: 1.NP; Object Layer Attributes #1, Požární odolnost: bez požadavku; Object Layer Attributes #1, Funkce (venkovní): Ne; Object Layer Attributes #1, Statická funkce: Ne; Object Layer Attributes #1, Vlhkostní namáhání oboustranné: Ne; Object Layer Attributes #1, Tloušťka opláštění: 2×12,5; Object Layer Attributes #1, Typ SDK desky: vysokopevnostní+bílá; Object Layer Attributes #1, Způsob opláštění: Jednostranné; Object Layer Attributes #1, Tloušťka izolace (2): 0; Object Layer Attributes #1, Objemová hmotnost izolace: 0; Object Layer Attributes #1, Typ profilu pro SDK: CW 100; Object Layer Attributes #1, Rozteč rastru: 625
SDK ŠACHTOVÁ STĚNA/SDK OPL. S PO | Půdorys 1.NP | SDK ŠACHTOVÁ STĚNA/SDK OPL. S PO 0.075 m |  | SDK ŠACHTOVÁ STĚNA/SDK OPL. S PO |  | 1464HWa1096312769 | m3 | Celá stěna | Nový | Suché stavební práce | SDK ŠACHTOVÁ STĚNA/SDK OPL. S PO | no | 1464Stě1096313041 | m3 | Stěna |  | 0.075 | 1.34 | 1.34 | 0.1 | 0.4 | 0.1 | 0.03 | 3.35 | NEMSOK - Object Layer Attributes #1, Kód prvku: SN07.03.0001; Object Layer Attributes #1, Podlaží: 1.NP; Object Layer Attributes #1, Požární odolnost: bez požadavku; Object Layer Attributes #1, Funkce (venkovní): Ne; Object Layer Attributes #1, Statická funkce: Ne; Object Layer Attributes #1, Vlhkostní namáhání oboustranné: Ne; Object Layer Attributes #1, Tloušťka opláštění: 2×12,5; Object Layer Attributes #1, Typ SDK desky: vysokopevnostní+bílá; Object Layer Attributes #1, Způsob opláštění: Jednostranné; Object Layer Attributes #1, Tloušťka izolace (2): 0; Object Layer Attributes #1, Objemová hmotnost izolace: 0; Object Layer Attributes #1, Typ profilu pro SDK: CW 100; Object Layer Attributes #1, Rozteč rastru: 625
ZDIVO Z CDm | Půdorys 2.NP | ZDIVO Z CDm 0.5 m | 1 | ZDIVO Z CDm | A | 1552HWa0000000009 | m3 | Celá stěna | Stávající | Zednické práce | ZDIVO Z CDm | yes | 1552Stě0000001510 | m3 | Stěna | 0 | 0.5 | 16.623 | 16.623 | 8.311 | 5.45 | 8.311 | 2.725 | 3.05
ZDIVO Z CDm | Půdorys 2.NP | ZDIVO Z CDm 0.5 m | 1 | ZDIVO Z CDm | A | 1552HWa0000000011 | m3 | Celá stěna | Stávající | Zednické práce | ZDIVO Z CDm | yes | 1552Stě0000001504 | m3 | Stěna | 0 | 0.5 | 10.675 | 10.675 | 5.337 | 3.5 | 5.337 | 1.75 | 3.05
ZDIVO Z CDm | Půdorys 2.NP | ZDIVO Z CDm |  | ZDIVO Z CDm | A | 1552HWa0000000002 | m3 | Celá stěna | Stávající | Zednické práce | ZDIVO Z CDm | yes | 1552Stě0000001494 | m3 | Stěna | 0 | 0.5 | 30.5 | 22.886 | 15.25 | 10 | 11.493 | 5 | 3.05
PLYNOSILIKÁT | Půdorys 2.NP | PLYNOSILIKÁT 0.32 m | 1 | PLYNOSILIKÁT | REI 180 | 1552HWa0798420388 | m3 | Celá stěna | Stávající | Zednické práce | PLYNOSILIKÁT |  | 1552Stě0798422159 | m3 | Stěna | 0.541 | 0.32 | 10.368 | 7.218 | 3.318 | 2.88 | 2.263 | 0.922 | 3.6 | Pset_WallCommon - AcousticRating: 48 dB
PLYNOSILIKÁT | Půdorys 2.NP | PLYNOSILIKÁT 0.32 m |  | PLYNOSILIKÁT | REI 180 | 1552HWa0798424104 | m3 | Celá stěna | Stávající | Zednické práce | PLYNOSILIKÁT | no | 1552Stě0798424105 | m3 | Stěna | 0.541 | 0.32 | 9.867 | 6.9 | 3.157 | 2.945 | 2.149 | 0.942 | 3.35 | Pset_WallCommon - AcousticRating: 48 dB
PLYNOSILIKÁT | Půdorys 2.NP | PLYNOSILIKÁT 0.32 m |  | PLYNOSILIKÁT | REI 180 | 1552HWa0798424109 | m3 | Celá stěna | Stávající | Zednické práce | PLYNOSILIKÁT | no | 1552Stě0798424110 | m3 | Stěna | 0.541 | 0.32 | 4.538 | 1.813 | 1.452 | 1.355 | 0.564 | 0.433 | 3.35 | Pset_WallCommon - AcousticRating: 48 dB
ZDIVO Z CDm | Půdorys 2.NP | ZDIVO Z CDm 0.35 m | 1 | ZDIVO Z CDm | A | 1552HWa0798434774 | m3 | Celá stěna | Stávající | Zednické práce | ZDIVO Z CDm | yes | 1552Stě0798434781 | m3 | Stěna | 0 | 0.35 | 1.34 | 1.34 | 0.469 | 0.4 | 0.469 | 0.14 | 3.35
ZELEZOBETONOVÁ KCE | Půdorys 2.NP | ZELEZOBETONOVÁ KCE 0.3 m | 1 | ZELEZOBETONOVÁ KCE | A | 1552HWa0000002122 | m3 | Celá stěna | Stávající | Betonářské práce | ZELEZOBETONOVÁ KCE |  | 1552Stě0000002123 | m3 | Stěna | 0 | 0.3 | 25.92 | 23.4 | 7.776 | 7.2 | 7.02 | 2.16 | 3.6
ZELEZOBETONOVÁ KCE | Půdorys 2.NP | ZELEZOBETONOVÁ KCE 0.3 m | 1 | ZELEZOBETONOVÁ KCE | A | 1552HWa0000002151 | m3 | Celá stěna | Stávající | Betonářské práce | ZELEZOBETONOVÁ KCE |  | 1552Stě0000002153 | m3 | Stěna | 0 | 0.3 | 19.44 | 19.44 | 5.832 | 5.4 | 5.832 | 1.62 | 3.6
ZELEZOBETONOVÁ KCE | Půdorys 2.NP | ZELEZOBETONOVÁ KCE 0.3 m | 1 | ZELEZOBETONOVÁ KCE | A | 1552HWa0000002169 | m3 | Celá stěna | Stávající | Betonářské práce | ZELEZOBETONOVÁ KCE |  | 1552Stě0000002170 | m3 | Stěna | 0 | 0.3 | 3.6 | 3.6 | 1.08 | 1 | 1.08 | 0.3 | 3.6
ZELEZOBETONOVÁ KCE | Půdorys 2.NP | ZELEZOBETONOVÁ KCE 0.3 m | 1 | ZELEZOBETONOVÁ KCE | A | 1552HWa0798419057 | m3 | Celá stěna | Stávající | Betonářské práce | ZELEZOBETONOVÁ KCE |  | 1552Stě0798419100 | m3 | Stěna | 0 | 0.3 | 3.6 | 3.6 | 1.08 | 1 | 1.08 | 0.3 | 3.6
ZELEZOBETONOVÁ KCE | Půdorys 2.NP | ZELEZOBETONOVÁ KCE 0.32 m | 1 | ZELEZOBETONOVÁ KCE | A | 1552HWa0000002203 | m3 | Celá stěna | Stávající | Betonářské práce | ZELEZOBETONOVÁ KCE |  | 1552Stě0000002204 | m3 | Stěna | 0 | 0.32 | 89.1 | 63.9 | 28.512 | 24.75 | 20.026 | 7.92 | 3.6
ZELEZOBETONOVÁ KCE | Půdorys 2.NP | ZELEZOBETONOVÁ KCE 0.3 m | 1 | ZELEZOBETONOVÁ KCE | A | 1552HWa0798420349 | m3 | Celá stěna | Stávající | Betonářské práce | ZELEZOBETONOVÁ KCE |  | 1552Stě0798420428 | m3 | Stěna | 0 | 0.3 | 2.592 | 2.592 | 0.778 | 0.72 | 0.778 | 0.216 | 3.6
ZELEZOBETONOVÁ KCE | Půdorys 2.NP | ZELEZOBETONOVÁ KCE 0.3 m | 1 | ZELEZOBETONOVÁ KCE | A | 1552HWa0798420350 | m3 | Celá stěna | Stávající | Betonářské práce | ZELEZOBETONOVÁ KCE |  | 1552Stě0798422156 | m3 | Stěna | 0 | 0.3 | 3.78 | 3.78 | 1.134 | 1.05 | 1.134 | 0.315 | 3.6
ZELEZOBETONOVÁ KCE | Půdorys 2.NP | ZELEZOBETONOVÁ KCE 0.3 m | 1 | ZELEZOBETONOVÁ KCE | A | 1552HWa0798420386 | m3 | Celá stěna | Stávající | Betonářské práce | ZELEZOBETONOVÁ KCE |  | 1552Stě0798420406 | m3 | Stěna | 0 | 0.3 | 3.672 | 3.672 | 1.102 | 1.02 | 1.102 | 0.306 | 3.6
ZELEZOBETONOVÁ KCE | Půdorys 2.NP | ZELEZOBETONOVÁ KCE 0.3 m | 1 | ZELEZOBETONOVÁ KCE | A | 1552HWa0798420416 | m3 | Celá stěna | Stávající | Betonářské práce | ZELEZOBETONOVÁ KCE |  | 1552Stě0798420436 | m3 | Stěna | 0 | 0.3 | 21.6 | 18.45 | 6.48 | 6 | 5.535 | 1.8 | 3.6
ZELEZOBETONOVÁ KCE | Půdorys 2.NP | ZELEZOBETONOVÁ KCE 0.3 m | 1 | ZELEZOBETONOVÁ KCE | A | 1552HWa0798420448 | m3 | Celá stěna | Stávající | Betonářské práce | ZELEZOBETONOVÁ KCE |  | 1552Stě0798422348 | m3 | Stěna | 0 | 0.3 | 3.78 | 3.78 | 1.134 | 1.05 | 1.134 | 0.315 | 3.6
ZELEZOBETONOVÁ KCE | Půdorys 2.NP | ZELEZOBETONOVÁ KCE 0.32 m | 1 | ZELEZOBETONOVÁ KCE | A | 1552HWa0798420457 | m3 | Celá stěna | Stávající | Betonářské práce | ZELEZOBETONOVÁ KCE |  | 1552Stě0798422024 | m3 | Stěna | 0 | 0.32 | 33.48 | 24.03 | 10.714 | 9.3 | 7.549 | 2.976 | 3.6
ZELEZOBETONOVÁ KCE | Půdorys 2.NP | ZELEZOBETONOVÁ KCE 0.2 m | 1 | ZELEZOBETONOVÁ KCE | A | 1552HWa0798422027 | m3 | Celá stěna | Stávající | Betonářské práce | ZELEZOBETONOVÁ KCE | yes | 1552Stě0798422459 | m3 | Stěna | 0 | 0.2 | 11.055 | 11.055 | 2.211 | 3.3 | 2.211 | 0.66 | 3.35
ZELEZOBETONOVÁ KCE | Půdorys 2.NP | ZELEZOBETONOVÁ KCE 0.2 m | 1 | ZELEZOBETONOVÁ KCE | A | 1552HWa0798422382 | m3 | Celá stěna | Stávající | Betonářské práce | ZELEZOBETONOVÁ KCE | yes | 1552Stě0798422455 | m3 | Stěna | 0 | 0.2 | 16.08 | 16.08 | 3.216 | 4.8 | 3.216 | 0.96 | 3.35
ZELEZOBETONOVÁ KCE | Půdorys 2.NP | ZELEZOBETONOVÁ KCE 0.2 m | 1 | ZELEZOBETONOVÁ KCE | A | 1552HWa0798422408 | m3 | Celá stěna | Stávající | Betonářské práce | ZELEZOBETONOVÁ KCE | yes | 1552Stě0798422428 | m3 | Stěna | 0 | 0.2 | 18.09 | 18.09 | 3.618 | 5.4 | 3.618 | 1.08 | 3.35
ZELEZOBETONOVÁ KCE | Půdorys 2.NP | ZELEZOBETONOVÁ KCE 0.2 m | 1 | ZELEZOBETONOVÁ KCE | A | 1552HWa0798423689 | m3 | Celá stěna | Stávající | Betonářské práce | ZELEZOBETONOVÁ KCE | yes | 1552Stě0798423690 | m3 | Stěna | 0 | 0.2 | 26.13 | 26.13 | 5.226 | 7.8 | 5.226 | 1.56 | 3.35
ZELEZOBETONOVÁ KCE | Půdorys 2.NP | ZELEZOBETONOVÁ KCE 0.3 m | 1 | ZELEZOBETONOVÁ KCE | A | 1552HWa0798420447 | m3 | Celá stěna | Stávající | Betonářské práce | ZELEZOBETONOVÁ KCE |  | 1552Stě0798422422 | m3 | Stěna | 0 | 0.3 | 3.672 | 3.672 | 1.102 | 1.02 | 1.102 | 0.306 | 3.6
ZELEZOBETONOVÁ KCE | Půdorys 2.NP | ZELEZOBETONOVÁ KCE 0.3 m | 1 | ZELEZOBETONOVÁ KCE | A | 1552HWa0798425129 | m3 | Celá stěna | Stávající | Betonářské práce | ZELEZOBETONOVÁ KCE |  | 1552Stě0798425130 | m3 | Stěna | 0 | 0.3 | 3.672 | 3.672 | 1.102 | 1.02 | 1.102 | 0.306 | 3.6
ZELEZOBETONOVÁ KCE | Půdorys 2.NP | ZELEZOBETONOVÁ KCE 0.3 m | 1 | ZELEZOBETONOVÁ KCE | A | 1552HWa0798419891 | m3 | Celá stěna | Stávající | Betonářské práce | ZELEZOBETONOVÁ KCE |  | 1552Stě0798419892 | m3 | Stěna | 0 | 0.3 | 55.08 | 45.63 | 16.524 | 15.3 | 13.689 | 4.59 | 3.6
ZELEZOBETONOVÁ KCE | Půdorys 2.NP | ZELEZOBETONOVÁ KCE 0.2 m | 1 | ZELEZOBETONOVÁ KCE | A | 1552HWa0798433250 | m3 | Celá stěna | Stávající | Betonářské práce | ZELEZOBETONOVÁ KCE | yes | 1552Stě0798434784 | m3 | Stěna | 0 | 0.2 | 10.05 | 10.05 | 2.01 | 3 | 2.01 | 0.6 | 3.35
ZDIVO Z CDm | Půdorys 2.NP | ZDIVO Z CDm 0.2 m | 1 | ZDIVO Z CDm | A | 1552HWa0798435782 | m3 | Celá stěna | Stávající | Zednické práce | ZDIVO Z CDm |  | 1552Stě0798435787 | m3 | Stěna | 0 | 0.2 | 1.34 | 1.34 | 0.268 | 0.4 | 0.268 | 0.08 | 3.35
ZDIVO Z CDm | Půdorys 2.NP | ZDIVO Z CDm 0.125 m | 1 | ZDIVO Z CDm | A | 1552HWa0798435789 | m3 | Celá stěna | Stávající | Zednické práce | ZDIVO Z CDm |  | 1552Stě0798435803 | m3 | Stěna | 0 | 0.125 | 1.106 | 1.106 | 0.138 | 0.33 | 0.138 | 0.041 | 3.35
ZDIVO Z CDm | Půdorys 2.NP | ZDIVO Z CDm 0.22 m |  | ZDIVO Z CDm | A | 1552HWa0798435792 | m3 | Celá stěna | Stávající | Zednické práce | ZDIVO Z CDm |  | 1552Stě0798435801 | m3 | Stěna | 0 | 0.22 | 3.099 | 3.099 | 0.682 | 0.925 | 0.682 | 0.203 | 3.35
ZDIVO Z CDm | Půdorys 2.NP | ZDIVO Z CDm 0.4 m |  | ZDIVO Z CDm | A | 1552HWa0798435796 | m3 | Celá stěna | Stávající | Zednické práce | ZDIVO Z CDm |  | 1552Stě0798435799 | m3 | Stěna | 0 | 0.4 | 2.412 | 2.412 | 0.965 | 0.72 | 0.965 | 0.288 | 3.35
ZDIVO Z CDm | Půdorys 2.NP | ZDIVO Z CDm 0.125 m | 1 | ZDIVO Z CDm | A | 1552HWa0798435791 | m3 | Celá stěna | Stávající | Zednické práce | ZDIVO Z CDm |  | 1552Stě0798435795 | m3 | Stěna | 0 | 0.125 | 1.005 | 1.005 | 0.126 | 0.3 | 0.126 | 0.037 | 3.35
ZDIVO Z CDm | Půdorys 2.NP | ZDIVO Z CDm 0.2 m | 1 | ZDIVO Z CDm | A | 1552HWa0798436005 | m3 | Celá stěna | Stávající | Zednické práce | ZDIVO Z CDm |  | 1552Stě0798436006 | m3 | Stěna | 0 | 0.2 | 0.737 | 0.737 | 0.147 | 0.22 | 0.147 | 0.044 | 3.35
ZDIVO Z CDm | Půdorys 2.NP | ZDIVO Z CDm 0.125 m | 1 | ZDIVO Z CDm | A | 1552HWa0798427990 | m3 | Celá stěna | Stávající | Zednické práce | ZDIVO Z CDm | yes | 1552Stě0798428007 | m3 | Stěna | 0 | 0.125 | 12.228 | 9.097 | 1.528 | 3.65 | 1.137 | 0.456 | 3.35
ZDIVO Z CDm | Půdorys 2.NP | ZDIVO Z CDm 0.125 m | 1 | ZDIVO Z CDm | A | 1552HWa0798428102 | m3 | Celá stěna | Stávající | Zednické práce | ZDIVO Z CDm | yes | 1552Stě0798428103 | m3 | Stěna | 0 | 0.125 | 0.586 | 0.586 | 0.073 | 0.175 | 0.073 | 0.022 | 3.35
ZDIVO Z CDm | Půdorys 2.NP | ZDIVO Z CDm 0.125 m | 1 | ZDIVO Z CDm | A | 1552HWa0798428130 | m3 | Celá stěna | Stávající | Zednické práce | ZDIVO Z CDm | yes | 1552Stě0798428131 | m3 | Stěna | 0 | 0.125 | 15.41 | 15.41 | 1.926 | 4.6 | 1.926 | 0.575 | 3.35
ZDIVO Z CDm | Půdorys 2.NP | ZDIVO Z CDm 0.125 m | 1 | ZDIVO Z CDm | A | 1552HWa0798428074 | m3 | Celá stěna | Stávající | Zednické práce | ZDIVO Z CDm | yes | 1552Stě0798428075 | m3 | Stěna | 0 | 0.125 | 5.444 | 5.444 | 0.68 | 1.625 | 0.68 | 0.203 | 3.35
ZDIVO Z CDm | Půdorys 2.NP | ZDIVO Z CDm 0.125 m | 1 | ZDIVO Z CDm | A | 1552HWa0798423654 | m3 | Celá stěna | Stávající | Zednické práce | ZDIVO Z CDm | yes | 1552Stě0798423655 | m3 | Stěna | 0 | 0.125 | 10.72 | 10.72 | 1.34 | 3.2 | 1.34 | 0.4 | 3.35
ZDIVO Z CDm | Půdorys 2.NP | ZDIVO Z CDm 0.125 m | 1 | ZDIVO Z CDm | A | 1552HWa0798436367 | m3 | Celá stěna | Stávající | Zednické práce | ZDIVO Z CDm | yes | 1552Stě0798436368 | m3 | Stěna | 0 | 0.125 | 1.742 | 1.742 | 0.218 | 0.52 | 0.218 | 0.065 | 3.35
ZDIVO Z CDm | Půdorys 2.NP | ZDIVO Z CDm 0.125 m | 1 | ZDIVO Z CDm | A | 1552HWa0798428050 | m3 | Celá stěna | Stávající | Zednické práce | ZDIVO Z CDm | yes | 1552Stě0798428051 | m3 | Stěna | 0 | 0.125 | 7.789 | 7.789 | 0.974 | 2.325 | 0.974 | 0.291 | 3.35
ZELEZOBETONOVÁ KCE | Půdorys 2.NP | ZELEZOBETONOVÁ KCE 0.32 m | 1 | ZELEZOBETONOVÁ KCE | A | 1552HWa0798422163 | m3 | Celá stěna | Stávající | Betonářské práce | ZELEZOBETONOVÁ KCE |  | 1552Stě0798422265 | m3 | Stěna | 0 | 0.32 | 63.922 | 44.55 | 20.455 | 17.756 | 13.924 | 5.682 | 3.6
ZELEZOBETONOVÁ KCE | Půdorys 2.NP | ZELEZOBETONOVÁ KCE 0.2 m |  | ZELEZOBETONOVÁ KCE | A | 1552HWa0798435724 | m3 | Celá stěna | Stávající | Betonářské práce | ZELEZOBETONOVÁ KCE | no | 1552Stě0798435733 | m3 | Stěna | 0 | 0.2 | 6.365 | 6.365 | 1.273 | 1.9 | 1.273 | 0.38 | 3.35
ZELEZOBETONOVÁ KCE | Půdorys 2.NP | ZELEZOBETONOVÁ KCE 0.2 m |  | ZELEZOBETONOVÁ KCE | A | 1552HWa0798435728 | m3 | Celá stěna | Stávající | Betonářské práce | ZELEZOBETONOVÁ KCE | no | 1552Stě0798435731 | m3 | Stěna | 0 | 0.2 | 6.365 | 6.365 | 1.273 | 1.9 | 1.273 | 0.38 | 3.35
ZELEZOBETONOVÁ KCE | Půdorys 2.NP | ZELEZOBETONOVÁ KCE 0.2 m |  | ZELEZOBETONOVÁ KCE | A | 1552HWa0798435722 | m3 | Celá stěna | Stávající | Betonářské práce | ZELEZOBETONOVÁ KCE | no | 1552Stě0798435735 | m3 | Stěna | 0 | 0.2 | 5.025 | 5.025 | 1.005 | 1.5 | 1.005 | 0.3 | 3.35
ZELEZOBETONOVÁ KCE | Půdorys 2.NP | ZELEZOBETONOVÁ KCE 0.2 m |  | ZELEZOBETONOVÁ KCE | A | 1552HWa0798435726 | m3 | Celá stěna | Stávající | Betonářské práce | ZELEZOBETONOVÁ KCE | no | 1552Stě0798435749 | m3 | Stěna | 0 | 0.2 | 16.08 | 16.08 | 3.216 | 4.8 | 3.216 | 0.96 | 3.35
ZELEZOBETONOVÁ KCE | Půdorys 2.NP | ZELEZOBETONOVÁ KCE 0.2 m |  | ZELEZOBETONOVÁ KCE | A | 1552HWa0798435736 | m3 | Celá stěna | Stávající | Betonářské práce | ZELEZOBETONOVÁ KCE | no | 1552Stě0798435747 | m3 | Stěna | 0 | 0.2 | 16.08 | 16.08 | 3.216 | 4.8 | 3.216 | 0.96 | 3.35
ZDIVO Z CDm | Půdorys 2.NP | ZDIVO Z CDm 0.125 m | 1 | ZDIVO Z CDm | A | 1552HWa0798427962 | m3 | Celá stěna | Stávající | Zednické práce | ZDIVO Z CDm | yes | 1552Stě0798427977 | m3 | Stěna | 0 | 0.125 | 33.751 | 31.024 | 4.219 | 10.075 | 3.878 | 1.259 | 3.35
ZDIVO Z CDm | Půdorys 2.NP | ZDIVO Z CDm 0.125 m | 1 | ZDIVO Z CDm | A | 1552HWa0798437616 | m3 | Celá stěna | Stávající | Zednické práce | ZDIVO Z CDm | yes | 1552Stě0798437617 | m3 | Stěna | 0 | 0.125 | 2.094 | 2.094 | 0.262 | 0.625 | 0.262 | 0.078 | 3.35
ZDIVO Z CDm | Půdorys 2.NP | ZDIVO Z CDm 0.125 m | 1 | ZDIVO Z CDm | A | 1552HWa0798437641 | m3 | Celá stěna | Stávající | Zednické práce | ZDIVO Z CDm | yes | 1552Stě0798437642 | m3 | Stěna | 0 | 0.125 | 2.01 | 2.01 | 0.251 | 0.6 | 0.251 | 0.075 | 3.35
ZDIVO Z CDm | Půdorys 2.NP | ZDIVO Z CDm 0.125 m | 1 | ZDIVO Z CDm | A | 1552HWa0798437648 | m3 | Celá stěna | Stávající | Zednické práce | ZDIVO Z CDm | yes | 1552Stě0798437649 | m3 | Stěna | 0 | 0.125 | 1.591 | 1.591 | 0.199 | 0.475 | 0.199 | 0.059 | 3.35
ZDIVO Z CDm | Půdorys 2.NP | ZDIVO Z CDm 0.125 m | 1 | ZDIVO Z CDm | A | 1552HWa0798437634 | m3 | Celá stěna | Stávající | Zednické práce | ZDIVO Z CDm | yes | 1552Stě0798437635 | m3 | Stěna | 0 | 0.125 | 11.474 | 8.747 | 1.434 | 3.425 | 1.093 | 0.428 | 3.35
ZDIVO Z CDm | Půdorys 2.NP | ZDIVO Z CDm 0.125 m | 1 | ZDIVO Z CDm | A | 1552HWa0798437878 | m3 | Celá stěna | Stávající | Zednické práce | ZDIVO Z CDm |  | 1552Stě0798437879 | m3 | Stěna | 0 | 0.125 | 1.424 | 1.424 | 0.178 | 0.425 | 0.178 | 0.053 | 3.35
ZDIVO Z CDm | Půdorys 2.NP | ZDIVO Z CDm 0.125 m | 1 | ZDIVO Z CDm | A | 1552HWa0798437890 | m3 | Celá stěna | Stávající | Zednické práce | ZDIVO Z CDm |  | 1552Stě0798437891 | m3 | Stěna | 0 | 0.125 | 3.015 | 3.015 | 0.377 | 0.9 | 0.377 | 0.113 | 3.35
ZDIVO Z CDm | Půdorys 2.NP | ZDIVO Z CDm 0.125 m | 1 | ZDIVO Z CDm | A | 1552HWa0798437915 | m3 | Celá stěna | Stávající | Zednické práce | ZDIVO Z CDm |  | 1552Stě0798437916 | m3 | Stěna | 0 | 0.125 | 9.631 | 7.611 | 1.204 | 2.875 | 0.951 | 0.359 | 3.35
ZDIVO Z CDm | Půdorys 2.NP | ZDIVO Z CDm 0.25 m | 1 | ZDIVO Z CDm | A | 1552HWa0798433254 | m3 | Celá stěna | Stávající | Zednické práce | ZDIVO Z CDm | yes | 1552Stě0798434779 | m3 | Stěna | 0 | 0.25 | 16.75 | 9.744 | 4.188 | 5 | 2.436 | 1.25 | 3.35
ZDIVO Z CDm | Půdorys 2.NP | ZDIVO Z CDm 0.35 m | 1 | ZDIVO Z CDm | A | 1552HWa0798434772 | m3 | Celá stěna | Stávající | Zednické práce | ZDIVO Z CDm | yes | 1552Stě0798434786 | m3 | Stěna | 0 | 0.35 | 1.34 | 1.34 | 0.469 | 0.4 | 0.469 | 0.14 | 3.35
ZELEZOBETONOVÁ KCE | Půdorys 2.NP | ZELEZOBETONOVÁ KCE 0.2 m | 1 | ZELEZOBETONOVÁ KCE | A | 1552HWa0798420500 | m3 | Celá stěna | Stávající | Betonářské práce | ZELEZOBETONOVÁ KCE | yes | 1552Stě0798422434 | m3 | Stěna | 0 | 0.2 | 12.06 | 12.06 | 2.412 | 3.6 | 2.412 | 0.72 | 3.35
ZELEZOBETONOVÁ KCE | Půdorys 2.NP | ZELEZOBETONOVÁ KCE 0.2 m | 1 | ZELEZOBETONOVÁ KCE | A | 1552HWa0798435738 | m3 | Celá stěna | Stávající | Betonářské práce | ZELEZOBETONOVÁ KCE | yes | 1552Stě0798435743 | m3 | Stěna | 0 | 0.2 | 12.06 | 12.06 | 2.412 | 3.6 | 2.412 | 0.72 | 3.35
ZELEZOBETONOVÁ KCE | Půdorys 2.NP | ZELEZOBETONOVÁ KCE 0.2 m | 1 | ZELEZOBETONOVÁ KCE | A | 1552HWa0798435740 | m3 | Celá stěna | Stávající | Betonářské práce | ZELEZOBETONOVÁ KCE | yes | 1552Stě0798435745 | m3 | Stěna | 0 | 0.2 | 13.4 | 13.4 | 2.68 | 4 | 2.68 | 0.8 | 3.35
ZDIVO Z CDm | Půdorys 2.NP | ZDIVO Z CDm 0.3 m | 1 | ZDIVO Z CDm | A | 1552HWa0798437856 | m3 | Celá stěna | Stávající | Zednické práce | ZDIVO Z CDm |  | 1552Stě0798437857 | m3 | Stěna | 0 | 0.3 | 3.015 | 3.015 | 0.905 | 0.9 | 0.905 | 0.27 | 3.35
ZDIVO Z CDm | Půdorys 2.NP | ZDIVO Z CDm 0.125 m | 1 | ZDIVO Z CDm | A | 1552HWa0798437869 | m3 | Celá stěna | Stávající | Zednické práce | ZDIVO Z CDm |  | 1552Stě0798437870 | m3 | Stěna | 0 | 0.125 | 8.107 | 8.107 | 1.013 | 2.42 | 1.013 | 0.302 | 3.35
PLYNOSILIKÁT | Půdorys 2.NP | PLYNOSILIKÁT 0.42 m | 1 | PLYNOSILIKÁT | REI 180 | 1552HWa0798439800 | m3 | Celá stěna | Stávající | Zednické práce | PLYNOSILIKÁT |  | 1552Stě0798439801 | m3 | Stěna | 0.541 | 0.42 | 3.672 | 1.662 | 1.542 | 1.02 | 0.799 | 0.428 | 3.6 | Pset_WallCommon - AcousticRating: 48 dB
PLYNOSILIKÁT | Půdorys 2.NP | PLYNOSILIKÁT 0.05 m | 1 | PLYNOSILIKÁT | REI 180 | 1552HWa0798439836 | m3 | Celá stěna | Stávající | Zednické práce | PLYNOSILIKÁT |  | 1552Stě0798439837 | m3 | Stěna | 0.541 | 0.05 | 1.188 | 1.188 | 0.059 | 0.33 | 0.059 | 0.017 | 3.6 | Pset_WallCommon - AcousticRating: 48 dB
PLYNOSILIKÁT | Půdorys 2.NP | PLYNOSILIKÁT 0.32 m | 1 | PLYNOSILIKÁT | REI 180 | 1552HWa0798422278 | m3 | Celá stěna | Stávající | Zednické práce | PLYNOSILIKÁT | no | 1552Stě0798422340 | m3 | Stěna | 0.541 | 0.32 | 56.16 | 42.194 | 17.971 | 15.6 | 13.502 | 4.992 | 3.6 | Pset_WallCommon - AcousticRating: 48 dB
ZELEZOBETONOVÁ KCE | Půdorys 2.NP | ZELEZOBETONOVÁ KCE 0.3 m | 1 | ZELEZOBETONOVÁ KCE | A | 1552HWa0798422133 | m3 | Celá stěna | Stávající | Betonářské práce | ZELEZOBETONOVÁ KCE |  | 1552Stě0798422154 | m3 | Stěna | 0 | 0.3 | 3.672 | 3.672 | 1.102 | 1.02 | 1.102 | 0.306 | 3.6
ZELEZOBETONOVÁ KCE | Půdorys 2.NP | ZELEZOBETONOVÁ KCE 0.3 m | 1 | ZELEZOBETONOVÁ KCE | A | 1552HWa0798422276 | m3 | Celá stěna | Stávající | Betonářské práce | ZELEZOBETONOVÁ KCE | no | 1552Stě0798422332 | m3 | Stěna | 0 | 0.3 | 3.672 | 3.672 | 1.102 | 1.02 | 1.102 | 0.306 | 3.6
ZELEZOBETONOVÁ KCE | Půdorys 2.NP | ZELEZOBETONOVÁ KCE 0.2 m | 1 | ZELEZOBETONOVÁ KCE | A | 1552HWa0798422011 | m3 | Celá stěna | Stávající | Betonářské práce | ZELEZOBETONOVÁ KCE | yes | 1552Stě0798422430 | m3 | Stěna | 0 | 0.2 | 16.75 | 16.75 | 3.35 | 5 | 3.35 | 1 | 3.35
ZELEZOBETONOVÁ KCE | Půdorys 2.NP | ZELEZOBETONOVÁ KCE 0.3 m | 1 | ZELEZOBETONOVÁ KCE | A | 1552HWa0798420352 | m3 | Celá stěna | Stávající | Betonářské práce | ZELEZOBETONOVÁ KCE |  | 1552Stě0798420414 | m3 | Stěna | 0 | 0.3 | 20.34 | 20.34 | 6.102 | 5.65 | 6.102 | 1.695 | 3.6
ZDIVO Z CDm | Půdorys 2.NP | ZDIVO Z CDm 0.48 m | 1 | ZDIVO Z CDm | A | 1552HWa0798441213 | m3 | Celá stěna | Stávající | Zednické práce | ZDIVO Z CDm |  | 1552Stě0798441214 | m3 | Stěna | 0 | 0.269 | 1.728 | 1.728 | 0.464 | 0.48 | 0.464 | 0.129 | 3.6
ZDIVO Z CDm | Půdorys 2.NP | ZDIVO Z CDm 0.48 m | 1 | ZDIVO Z CDm | A | 1552HWa0798435974 | m3 | Celá stěna | Stávající | Zednické práce | ZDIVO Z CDm |  | 1552Stě0798435975 | m3 | Stěna | 0 | 0.48 | 1.575 | 1.44 | 0.756 | 0.438 | 0.756 | 0.21 | 3.6
PÓROBETONOVÉ ZDIVO | Půdorys 2.NP | PÓROBETONOVÉ ZDIVO 0.3 m | 1 | PÓROBETONOVÉ ZDIVO | REI 180 | 1552HWa0798441361 | m3 | Celá stěna | Stávající | Zednické práce | PÓROBETONOVÉ ZDIVO |  | 1552Stě0798441368 | m3 | Stěna | 0.541 | 0.3 | 1.44 | 1.44 | 0.432 | 0.4 | 0.432 | 0.12 | 3.6 | Pset_WallCommon - AcousticRating: 48 dB
PÓROBETONOVÉ ZDIVO | Půdorys 2.NP | PÓROBETONOVÉ ZDIVO 0.25 m | 1 | PÓROBETONOVÉ ZDIVO | REI 180 | 1552HWa0798441363 | m3 | Celá stěna | Stávající | Zednické práce | PÓROBETONOVÉ ZDIVO |  | 1552Stě0798441366 | m3 | Stěna | 0.541 | 0.25 | 1.8 | 1.8 | 0.45 | 0.5 | 0.45 | 0.125 | 3.6 | Pset_WallCommon - AcousticRating: 48 dB
PÓROBETONOVÉ ZDIVO | Půdorys 2.NP | PÓROBETONOVÉ ZDIVO 0.25 m | 1 | PÓROBETONOVÉ ZDIVO | REI 180 | 1552HWa0798441369 | m3 | Celá stěna | Stávající | Zednické práce | PÓROBETONOVÉ ZDIVO |  | 1552Stě0798441372 | m3 | Stěna | 0.541 | 0.25 | 1.26 | 1.26 | 0.315 | 0.35 | 0.315 | 0.088 | 3.6 | Pset_WallCommon - AcousticRating: 48 dB
PÓROBETONOVÉ ZDIVO | Půdorys 2.NP | PÓROBETONOVÉ ZDIVO 0.33 m | 1 | PÓROBETONOVÉ ZDIVO | REI 180 | 1552HWa0798441387 | m3 | Celá stěna | Stávající | Zednické práce | PÓROBETONOVÉ ZDIVO | no | 1552Stě0798441388 | m3 | Stěna | 0.541 | 0.33 | 1.98 | 1.98 | 0.653 | 0.55 | 0.653 | 0.181 | 3.6 | Pset_WallCommon - AcousticRating: 48 dB
ZDIVO Z CDm | Půdorys 2.NP | ZDIVO Z CDm 0.125 m | 1 | ZDIVO Z CDm | A | 1552HWa0798441395 | m3 | Celá stěna | Stávající | Zednické práce | ZDIVO Z CDm | yes | 1552Stě0798441396 | m3 | Stěna | 0 | 0.125 | 6.114 | 5.394 | 0.764 | 1.825 | 0.674 | 0.228 | 3.35
ZDIVO Z CDm | Půdorys 2.NP | ZDIVO Z CDm 0.125 m | 1 | ZDIVO Z CDm | A | 1552HWa0798441400 | m3 | Celá stěna | Stávající | Zednické práce | ZDIVO Z CDm | yes | 1552Stě0798441401 | m3 | Stěna | 0 | 0.125 | 3.099 | 3.099 | 0.387 | 0.925 | 0.387 | 0.116 | 3.35
ZDIVO Z CDm | Půdorys 2.NP | ZDIVO Z CDm 0.125 m | 1 | ZDIVO Z CDm | A | 1552HWa0798441410 | m3 | Celá stěna | Stávající | Zednické práce | ZDIVO Z CDm | yes | 1552Stě0798441411 | m3 | Stěna | 0 | 0.125 | 6.114 | 6.114 | 0.764 | 1.825 | 0.764 | 0.228 | 3.35
ZDIVO Z CDm | Půdorys 2.NP | ZDIVO Z CDm 0.125 m | 1 | ZDIVO Z CDm | A | 1552HWa0798441422 | m3 | Celá stěna | Stávající | Zednické práce | ZDIVO Z CDm | yes | 1552Stě0798441423 | m3 | Stěna | 0 | 0.125 | 2.027 | 1.759 | 0.253 | 0.605 | 0.253 | 0.076 | 3.35
ZDIVO Z CDm | Půdorys 2.NP | ZDIVO Z CDm 0.125 m | 1 | ZDIVO Z CDm | A | 1552HWa0798441502 | m3 | Celá stěna | Stávající | Zednické práce | ZDIVO Z CDm | yes | 1552Stě0798441503 | m3 | Stěna | 0 | 0.125 | 6.03 | 4.68 | 0.754 | 1.8 | 0.585 | 0.225 | 3.35
ZDIVO Z CDm | Půdorys 2.NP | ZDIVO Z CDm 0.125 m | 1 | ZDIVO Z CDm | A | 1552HWa0798441563 | m3 | Celá stěna | Stávající | Zednické práce | ZDIVO Z CDm | yes | 1552Stě0798441564 | m3 | Stěna | 0 | 0.125 | 13.651 | 10.951 | 1.706 | 4.075 | 1.369 | 0.509 | 3.35
ZDIVO Z CDm | Půdorys 2.NP | ZDIVO Z CDm 0.125 m | 1 | ZDIVO Z CDm | A | 1552HWa0798441509 | m3 | Celá stěna | Stávající | Zednické práce | ZDIVO Z CDm | yes | 1552Stě0798441510 | m3 | Stěna | 0 | 0.125 | 3.852 | 3.853 | 0.482 | 1.15 | 0.482 | 0.144 | 3.35
ZDIVO Z CDm | Půdorys 2.NP | ZDIVO Z CDm 0.125 m | 1 | ZDIVO Z CDm | A | 1552HWa0798441520 | m3 | Celá stěna | Stávající | Zednické práce | ZDIVO Z CDm | yes | 1552Stě0798441521 | m3 | Stěna | 0 | 0.125 | 1.759 | 1.759 | 0.22 | 0.525 | 0.22 | 0.066 | 3.35
ZDIVO Z CDm | Půdorys 2.NP | ZDIVO Z CDm 0.125 m | 1 | ZDIVO Z CDm | A | 1552HWa0798441534 | m3 | Celá stěna | Stávající | Zednické práce | ZDIVO Z CDm | yes | 1552Stě0798441535 | m3 | Stěna | 0 | 0.125 | 14.74 | 14.74 | 1.842 | 4.4 | 1.842 | 0.55 | 3.35
ZDIVO Z CDm | Půdorys 2.NP | ZDIVO Z CDm 0.125 m | 1 | ZDIVO Z CDm | A | 1552HWa0798441599 | m3 | Celá stěna | Stávající | Zednické práce | ZDIVO Z CDm | yes | 1552Stě0798441600 | m3 | Stěna | 0 | 0.125 | 7.286 | 7.286 | 0.911 | 2.175 | 0.911 | 0.272 | 3.35
ZDIVO Z CDm | Půdorys 2.NP | ZDIVO Z CDm 0.125 m | 1 | ZDIVO Z CDm | A | 1552HWa0798441611 | m3 | Celá stěna | Stávající | Zednické práce | ZDIVO Z CDm | yes | 1552Stě0798441612 | m3 | Stěna | 0 | 0.125 | 1.759 | 1.759 | 0.22 | 0.525 | 0.22 | 0.066 | 3.35
ZDIVO Z CDm | Půdorys 2.NP | ZDIVO Z CDm 0.125 m | 1 | ZDIVO Z CDm | A | 1552HWa0798441623 | m3 | Celá stěna | Stávající | Zednické práce | ZDIVO Z CDm | yes | 1552Stě0798441624 | m3 | Stěna | 0 | 0.125 | 6.868 | 6.148 | 0.858 | 2.05 | 0.768 | 0.256 | 3.35
ZDIVO Z CDm | Půdorys 2.NP | ZDIVO Z CDm 0.125 m | 1 | ZDIVO Z CDm | A | 1552HWa0798441654 | m3 | Celá stěna | Stávající | Zednické práce | ZDIVO Z CDm | yes | 1552Stě0798441655 | m3 | Stěna | 0 | 0.125 | 24.807 | 22.787 | 3.101 | 7.405 | 2.848 | 0.926 | 3.35
ZDIVO Z CDm | Půdorys 2.NP | ZDIVO Z CDm 0.125 m | 1 | ZDIVO Z CDm | A | 1552HWa0798441918 | m3 | Celá stěna | Stávající | Zednické práce | ZDIVO Z CDm | yes | 1552Stě0798441919 | m3 | Stěna | 0 | 0.125 | 1.675 | 1.675 | 0.209 | 0.5 | 0.209 | 0.063 | 3.35
PÓROBETONOVÉ ZDIVO | Půdorys 2.NP | PÓROBETONOVÉ ZDIVO 0.12 m | 1 | PÓROBETONOVÉ ZDIVO | EI 120 | 1552HWa0798441930 | m3 | Celá stěna | Stávající | Zednické práce | PÓROBETONOVÉ ZDIVO |  | 1552Stě0798441933 | m2 | Stěna | 1.111 | 0.12 | 15.41 | 15.41 | 1.849 | 4.6 | 1.849 | 0.552 | 3.35 | Pset_WallCommon - AcousticRating: 37 dB
ZDIVO Z CDm | Půdorys 2.NP | ZDIVO Z CDm 0.125 m | 1 | ZDIVO Z CDm | A | 1552HWa0798441962 | m3 | Celá stěna | Stávající | Zednické práce | ZDIVO Z CDm | yes | 1552Stě0798441963 | m3 | Stěna | 0 | 0.125 | 1.273 | 1.273 | 0.159 | 0.38 | 0.159 | 0.048 | 3.35
ZDIVO Z CDm | Půdorys 2.NP | ZDIVO Z CDm 0.125 m | 1 | ZDIVO Z CDm | A | 1552HWa0798441974 | m3 | Celá stěna | Stávající | Zednické práce | ZDIVO Z CDm | yes | 1552Stě0798441975 | m3 | Stěna | 0 | 0.125 | 8.04 | 6.626 | 1.005 | 2.4 | 0.828 | 0.3 | 3.35
ZDIVO Z CDm | Půdorys 2.NP | ZDIVO Z CDm 0.125 m | 1 | ZDIVO Z CDm | A | 1552HWa0798441984 | m3 | Celá stěna | Stávající | Zednické práce | ZDIVO Z CDm | yes | 1552Stě0798441985 | m3 | Stěna | 0 | 0.125 | 23.115 | 18.873 | 2.889 | 6.9 | 2.359 | 0.863 | 3.35
ZDIVO Z CDm | Půdorys 2.NP | ZDIVO Z CDm 0.125 m | 1 | ZDIVO Z CDm | A | 1552HWa0798441642 | m3 | Celá stěna | Stávající | Zednické práce | ZDIVO Z CDm | yes | 1552Stě0798441643 | m3 | Stěna | 0 | 0.125 | 23.534 | 18.56 | 2.942 | 7.025 | 2.32 | 0.878 | 3.35
ZDIVO Z CDm | Půdorys 2.NP | ZDIVO Z CDm 0.125 m | 1 | ZDIVO Z CDm | A | 1552HWa0798442047 | m3 | Celá stěna | Stávající | Zednické práce | ZDIVO Z CDm | yes | 1552Stě0798442048 | m3 | Stěna | 0 | 0.125 | 0.67 | 0.67 | 0.084 | 0.2 | 0.084 | 0.025 | 3.35
ZDIVO Z CDm | Půdorys 2.NP | ZDIVO Z CDm 0.125 m | 1 | ZDIVO Z CDm | A | 1552HWa0798442059 | m3 | Celá stěna | Stávající | Zednické práce | ZDIVO Z CDm | yes | 1552Stě0798442060 | m3 | Stěna | 0 | 0.125 | 0.67 | 0.67 | 0.084 | 0.2 | 0.084 | 0.025 | 3.35
ZDIVO Z CDm | Půdorys 2.NP | ZDIVO Z CDm 0.125 m | 1 | ZDIVO Z CDm | A | 1552HWa0798442083 | m3 | Celá stěna | Stávající | Zednické práce | ZDIVO Z CDm | yes | 1552Stě0798442084 | m3 | Stěna | 0 | 0.125 | 6.968 | 6.968 | 0.871 | 2.08 | 0.871 | 0.26 | 3.35
ZDIVO Z CDm | Půdorys 2.NP | ZDIVO Z CDm 0.125 m | 1 | ZDIVO Z CDm | A | 1552HWa0798442093 | m3 | Celá stěna | Stávající | Zednické práce | ZDIVO Z CDm | yes | 1552Stě0798442094 | m3 | Stěna | 0 | 0.125 | 3.266 | 1.852 | 0.408 | 0.975 | 0.232 | 0.122 | 3.35
ZDIVO Z CDm | Půdorys 2.NP | ZDIVO Z CDm 0.125 m | 1 | ZDIVO Z CDm | A | 1552HWa0798442103 | m3 | Celá stěna | Stávající | Zednické práce | ZDIVO Z CDm | yes | 1552Stě0798442104 | m3 | Stěna | 0 | 0.125 | 10.636 | 10.636 | 1.33 | 3.175 | 1.33 | 0.397 | 3.35
ZDIVO Z CDm | Půdorys 2.NP | ZDIVO Z CDm 0.125 m | 1 | ZDIVO Z CDm | A | 1552HWa0798442114 | m3 | Celá stěna | Stávající | Zednické práce | ZDIVO Z CDm | yes | 1552Stě0798442115 | m3 | Stěna | 0 | 0.125 | 2.847 | 1.434 | 0.356 | 0.85 | 0.179 | 0.106 | 3.35
ZDIVO Z CDm | Půdorys 2.NP | ZDIVO Z CDm 0.125 m | 1 | ZDIVO Z CDm | A | 1552HWa0798442130 | m3 | Celá stěna | Stávající | Zednické práce | ZDIVO Z CDm | yes | 1552Stě0798442131 | m3 | Stěna | 0 | 0.125 | 2.847 | 2.848 | 0.356 | 0.85 | 0.356 | 0.106 | 3.35
ZDIVO Z CDm | Půdorys 2.NP | ZDIVO Z CDm 0.125 m | 1 | ZDIVO Z CDm | A | 1552HWa0798442179 | m3 | Celá stěna | Stávající | Zednické práce | ZDIVO Z CDm | yes | 1552Stě0798442180 | m3 | Stěna | 0 | 0.125 | 6.616 | 5.176 | 0.827 | 1.975 | 0.647 | 0.247 | 3.35
ZDIVO Z CDm | Půdorys 2.NP | ZDIVO Z CDm 0.125 m | 1 | ZDIVO Z CDm | A | 1552HWa0798442189 | m3 | Celá stěna | Stávající | Zednické práce | ZDIVO Z CDm | yes | 1552Stě0798442190 | m3 | Stěna | 0 | 0.125 | 5.025 | 5.025 | 0.628 | 1.5 | 0.628 | 0.188 | 3.35
ZDIVO Z CDm | Půdorys 2.NP | ZDIVO Z CDm 0.125 m | 1 | ZDIVO Z CDm | A | 1552HWa0798442199 | m3 | Celá stěna | Stávající | Zednické práce | ZDIVO Z CDm | yes | 1552Stě0798442200 | m3 | Stěna | 0 | 0.125 | 6.951 | 6.951 | 0.869 | 2.075 | 0.869 | 0.259 | 3.35
ZDIVO Z CDm | Půdorys 2.NP | ZDIVO Z CDm 0.125 m | 1 | ZDIVO Z CDm | A | 1552HWa0798442209 | m3 | Celá stěna | Stávající | Zednické práce | ZDIVO Z CDm | yes | 1552Stě0798442210 | m3 | Stěna | 0 | 0.125 | 8.878 | 6.05 | 1.11 | 2.65 | 0.756 | 0.331 | 3.35
ZDIVO Z CDm | Půdorys 2.NP | ZDIVO Z CDm 0.125 m | 1 | ZDIVO Z CDm | A | 1552HWa0798442260 | m3 | Celá stěna | Stávající | Zednické práce | ZDIVO Z CDm | yes | 1552Stě0798442261 | m3 | Stěna | 0 | 0.125 | 7.219 | 5.805 | 0.902 | 2.155 | 0.726 | 0.269 | 3.35
ZDIVO Z CDm | Půdorys 2.NP | ZDIVO Z CDm 0.125 m | 1 | ZDIVO Z CDm | A | 1552HWa0798443046 | m3 | Celá stěna | Stávající | Zednické práce | ZDIVO Z CDm | yes | 1552Stě0798443047 | m3 | Stěna | 0 | 0.125 | 3.015 | 3.015 | 0.377 | 0.9 | 0.377 | 0.113 | 3.35
ZDIVO Z CDm | Půdorys 2.NP | ZDIVO Z CDm 0.125 m | 1 | ZDIVO Z CDm | A | 1552HWa0798443053 | m3 | Celá stěna | Stávající | Zednické práce | ZDIVO Z CDm | yes | 1552Stě0798443054 | m3 | Stěna | 0 | 0.125 | 0.921 | 0.921 | 0.115 | 0.275 | 0.115 | 0.034 | 3.35
ZDIVO Z CDm | Půdorys 2.NP | ZDIVO Z CDm 0.125 m | 1 | ZDIVO Z CDm | A | 1552HWa0798443069 | m3 | Celá stěna | Stávající | Zednické práce | ZDIVO Z CDm | yes | 1552Stě0798443070 | m3 | Stěna | 0 | 0.125 | 2.178 | 2.178 | 0.272 | 0.65 | 0.272 | 0.081 | 3.35
ZDIVO Z CDm | Půdorys 2.NP | ZDIVO Z CDm 0.125 m | 1 | ZDIVO Z CDm | A | 1552HWa0798443079 | m3 | Celá stěna | Stávající | Zednické práce | ZDIVO Z CDm | yes | 1552Stě0798443080 | m3 | Stěna | 0 | 0.125 | 4.439 | 4.439 | 0.555 | 1.325 | 0.555 | 0.166 | 3.35
ZDIVO Z CDm | Půdorys 2.NP | ZDIVO Z CDm 0.125 m | 1 | ZDIVO Z CDm | A | 1552HWa0798442071 | m3 | Celá stěna | Stávající | Zednické práce | ZDIVO Z CDm | yes | 1552Stě0798442072 | m3 | Stěna | 0 | 0.125 | 13.919 | 13.919 | 1.74 | 4.155 | 1.74 | 0.519 | 3.35
ZDIVO Z CDm | Půdorys 2.NP | ZDIVO Z CDm 0.125 m | 1 | ZDIVO Z CDm | A | 1552HWa0798443240 | m3 | Celá stěna | Stávající | Zednické práce | ZDIVO Z CDm | yes | 1552Stě0798443241 | m3 | Stěna | 0 | 0.125 | 1.675 | 1.675 | 0.209 | 0.5 | 0.209 | 0.062 | 3.35
ZDIVO Z CDm | Půdorys 2.NP | ZDIVO Z CDm 0.125 m | 1 | ZDIVO Z CDm | A | 1552HWa0798443250 | m3 | Celá stěna | Stávající | Zednické práce | ZDIVO Z CDm | yes | 1552Stě0798443251 | m3 | Stěna | 0 | 0.125 | 1.256 | 1.256 | 0.157 | 0.375 | 0.157 | 0.047 | 3.35
ZDIVO Z CDm | Půdorys 2.NP | ZDIVO Z CDm 0.125 m |  | ZDIVO Z CDm | A | 1552HWa0798443303 | m3 | Celá stěna | Stávající | Zednické práce | ZDIVO Z CDm |  | 1552Stě0798443321 | m3 | Stěna | 0 | 0.125 | 1.067 | 1.068 | 0.133 | 0.35 | 0.133 | 0.044 | 3.05
ZDIVO Z CDm | Půdorys 2.NP | ZDIVO Z CDm 0.125 m |  | ZDIVO Z CDm | A | 1552HWa0798443299 | m3 | Celá stěna | Stávající | Zednické práce | ZDIVO Z CDm |  | 1552Stě0798443306 | m3 | Stěna | 0 | 0.125 | 0.915 | 0.915 | 0.114 | 0.3 | 0.114 | 0.037 | 3.05
ZDIVO Z CDm | Půdorys 2.NP | ZDIVO Z CDm 0.125 m |  | ZDIVO Z CDm | A | 1552HWa0798443302 | m3 | Celá stěna | Stávající | Zednické práce | ZDIVO Z CDm |  | 1552Stě0798443325 | m3 | Stěna | 0 | 0.125 | 6.765 | 6.045 | 0.846 | 2.05 | 0.756 | 0.256 | 3.3
ZDIVO Z CDm | Půdorys 2.NP | ZDIVO Z CDm 0.125 m |  | ZDIVO Z CDm | A | 1552HWa0798443322 | m3 | Celá stěna | Stávající | Zednické práce | ZDIVO Z CDm |  | 1552Stě0798443327 | m3 | Stěna | 0 | 0.125 | 0.99 | 0.99 | 0.124 | 0.3 | 0.124 | 0.037 | 3.3
ZDIVO Z CDm | Půdorys 2.NP | ZDIVO Z CDm 0.125 m |  | ZDIVO Z CDm | A | 1552HWa0000000014 | m3 | Celá stěna | Stávající | Zednické práce | ZDIVO Z CDm | no | 1552Stě0000001500 | m3 | Stěna | 0 | 0.125 | 7.92 | 7.92 | 0.99 | 2.4 | 0.99 | 0.3 | 3.3
ZDIVO Z CDm | Půdorys 2.NP | ZDIVO Z CDm 0.125 m | 1 | ZDIVO Z CDm | A | 1552HWa0798443408 | m3 | Celá stěna | Stávající | Zednické práce | ZDIVO Z CDm | yes | 1552Stě0798443426 | m3 | Stěna | 0 | 0.125 | 1.675 | 1.675 | 0.209 | 0.5 | 0.209 | 0.062 | 3.35
ZDIVO Z CDm | Půdorys 2.NP | ZDIVO Z CDm 0.125 m | 1 | ZDIVO Z CDm | A | 1552HWa0798443410 | m3 | Celá stěna | Stávající | Zednické práce | ZDIVO Z CDm | yes | 1552Stě0798443415 | m3 | Stěna | 0 | 0.125 | 0.335 | 0.335 | 0.042 | 0.1 | 0.042 | 0.013 | 3.35
ZDIVO Z CDm | Půdorys 2.NP | ZDIVO Z CDm 0.125 m | 1 | ZDIVO Z CDm | A | 1552HWa0798443412 | m3 | Celá stěna | Stávající | Zednické práce | ZDIVO Z CDm | yes | 1552Stě0798443428 | m3 | Stěna | 0 | 0.125 | 3.015 | 3.015 | 0.377 | 0.9 | 0.377 | 0.113 | 3.35
ZDIVO Z CDm | Půdorys 2.NP | ZDIVO Z CDm 0.125 m | 1 | ZDIVO Z CDm | A | 1552HWa0798443416 | m3 | Celá stěna | Stávající | Zednické práce | ZDIVO Z CDm | yes | 1552Stě0798443424 | m3 | Stěna | 0 | 0.125 | 4.355 | 3.865 | 0.544 | 1.3 | 0.483 | 0.163 | 3.35
ZDIVO Z CDm | Půdorys 2.NP | ZDIVO Z CDm 0.125 m | 1 | ZDIVO Z CDm | A | 1552HWa0798443506 | m3 | Celá stěna | Stávající | Zednické práce | ZDIVO Z CDm | yes | 1552Stě0798443507 | m3 | Stěna | 0 | 0.125 | 5.611 | 5.611 | 0.701 | 1.675 | 0.701 | 0.209 | 3.35
ZDIVO Z CDm | Půdorys 2.NP | ZDIVO Z CDm 0.125 m | 1 | ZDIVO Z CDm | A | 1552HWa0798443521 | m3 | Celá stěna | Stávající | Zednické práce | ZDIVO Z CDm | yes | 1552Stě0798443522 | m3 | Stěna | 0 | 0.125 | 2.764 | 2.764 | 0.345 | 0.825 | 0.345 | 0.103 | 3.35
ZDIVO Z CDm | Půdorys 2.NP | ZDIVO Z CDm 0.125 m | 1 | ZDIVO Z CDm | A | 1552HWa0798443531 | m3 | Celá stěna | Stávající | Zednické práce | ZDIVO Z CDm | yes | 1552Stě0798443532 | m3 | Stěna | 0 | 0.125 | 1.256 | 1.256 | 0.157 | 0.375 | 0.157 | 0.047 | 3.35
ZDIVO Z CDm | Půdorys 2.NP | ZDIVO Z CDm 0.125 m | 1 | ZDIVO Z CDm | A | 1552HWa0798443585 | m3 | Celá stěna | Stávající | Zednické práce | ZDIVO Z CDm | yes | 1552Stě0798443586 | m3 | Stěna | 0 | 0.125 | 2.01 | 2.01 | 0.251 | 0.6 | 0.251 | 0.075 | 3.35
ZDIVO Z CDm | Půdorys 2.NP | ZDIVO Z CDm 0.125 m | 1 | ZDIVO Z CDm | A | 1552HWa0798443590 | m3 | Celá stěna | Stávající | Zednické práce | ZDIVO Z CDm | yes | 1552Stě0798443591 | m3 | Stěna | 0 | 0.125 | 1.926 | 1.926 | 0.241 | 0.575 | 0.241 | 0.072 | 3.35
ZDIVO Z CDm | Půdorys 2.NP | ZDIVO Z CDm 0.125 m | 1 | ZDIVO Z CDm | A | 1552HWa0798443601 | m3 | Celá stěna | Stávající | Zednické práce | ZDIVO Z CDm | yes | 1552Stě0798443602 | m3 | Stěna | 0 | 0.125 | 1.591 | 1.591 | 0.199 | 0.475 | 0.199 | 0.059 | 3.35
ZDIVO Z CDm | Půdorys 2.NP | ZDIVO Z CDm 0.125 m | 1 | ZDIVO Z CDm | A | 1552HWa0798443808 | m3 | Celá stěna | Stávající | Zednické práce | ZDIVO Z CDm |  | 1552Stě0798443809 | m3 | Stěna | 0 | 0.125 | 4.104 | 4.104 | 0.513 | 1.225 | 0.513 | 0.153 | 3.35
ZDIVO Z CDm | Půdorys 2.NP | ZDIVO Z CDm 0.125 m | 1 | ZDIVO Z CDm | A | 1552HWa0798443818 | m3 | Celá stěna | Stávající | Zednické práce | ZDIVO Z CDm |  | 1552Stě0798443819 | m3 | Stěna | 0 | 0.125 | 1.759 | 1.759 | 0.22 | 0.525 | 0.22 | 0.066 | 3.35
ZDIVO Z CDm | Půdorys 2.NP | ZDIVO Z CDm 0.125 m | 1 | ZDIVO Z CDm | A | 1552HWa0798443828 | m3 | Celá stěna | Stávající | Zednické práce | ZDIVO Z CDm |  | 1552Stě0798443829 | m3 | Stěna | 0 | 0.125 | 3.685 | 2.965 | 0.461 | 1.1 | 0.371 | 0.137 | 3.35
ZDIVO Z CDm | Půdorys 2.NP | ZDIVO Z CDm 0.125 m | 1 | ZDIVO Z CDm | A | 1552HWa0798443845 | m3 | Celá stěna | Stávající | Zednické práce | ZDIVO Z CDm |  | 1552Stě0798443846 | m3 | Stěna | 0 | 0.125 | 3.199 | 3.199 | 0.4 | 0.955 | 0.4 | 0.119 | 3.35
ZDIVO Z CDm | Půdorys 2.NP | ZDIVO Z CDm 0.125 m | 1 | ZDIVO Z CDm | A | 1552HWa0798443854 | m3 | Celá stěna | Stávající | Zednické práce | ZDIVO Z CDm |  | 1552Stě0798443855 | m3 | Stěna | 0 | 0.125 | 1.759 | 1.759 | 0.22 | 0.525 | 0.22 | 0.066 | 3.35
ZDIVO Z CDm | Půdorys 2.NP | ZDIVO Z CDm 0.125 m | 1 | ZDIVO Z CDm | A | 1552HWa0798443866 | m3 | Celá stěna | Stávající | Zednické práce | ZDIVO Z CDm |  | 1552Stě0798443867 | m3 | Stěna | 0 | 0.125 | 2.781 | 2.781 | 0.348 | 0.83 | 0.348 | 0.104 | 3.35
ZDIVO Z CDm | Půdorys 2.NP | ZDIVO Z CDm 0.125 m | 1 | ZDIVO Z CDm | A | 1552HWa0798443882 | m3 | Celá stěna | Stávající | Zednické práce | ZDIVO Z CDm |  | 1552Stě0798443883 | m3 | Stěna | 0 | 0.125 | 4.104 | 3.384 | 0.513 | 1.225 | 0.423 | 0.153 | 3.35
ZDIVO Z CDm | Půdorys 2.NP | ZDIVO Z CDm 0.125 m | 1 | ZDIVO Z CDm | A | 1552HWa0798443892 | m3 | Celá stěna | Stávající | Zednické práce | ZDIVO Z CDm |  | 1552Stě0798443893 | m3 | Stěna | 0 | 0.125 | 1.759 | 1.759 | 0.22 | 0.525 | 0.22 | 0.066 | 3.35
ZDIVO Z CDm | Půdorys 2.NP | ZDIVO Z CDm 0.125 m | 1 | ZDIVO Z CDm | A | 1552HWa0798443902 | m3 | Celá stěna | Stávající | Zednické práce | ZDIVO Z CDm |  | 1552Stě0798443903 | m3 | Stěna | 0 | 0.125 | 3.685 | 3.685 | 0.461 | 1.1 | 0.461 | 0.138 | 3.35
ZDIVO Z CDm | Půdorys 2.NP | ZDIVO Z CDm 0.125 m | 1 | ZDIVO Z CDm | A | 1552HWa0798443950 | m3 | Celá stěna | Stávající | Zednické práce | ZDIVO Z CDm |  | 1552Stě0798443951 | m3 | Stěna | 0 | 0.125 | 3.266 | 3.266 | 0.408 | 0.975 | 0.408 | 0.122 | 3.35
ZELEZOBETONOVÁ KCE | Půdorys 2.NP | ZELEZOBETONOVÁ KCE 0.32 m | 1 | ZELEZOBETONOVÁ KCE | A | 1552HWa0798419059 | m3 | Celá stěna | Stávající | Betonářské práce | ZELEZOBETONOVÁ KCE |  | 1552Stě0798419099 | m3 | Stěna | 0 | 0.32 | 86.4 | 63.213 | 27.648 | 24 | 19.853 | 7.68 | 3.6
ZDIVO Z CDm | Půdorys 2.NP | ZDIVO Z CDm 0.125 m | 1 | ZDIVO Z CDm | A | 1552HWa0798443960 | m3 | Celá stěna | Stávající | Zednické práce | ZDIVO Z CDm |  | 1552Stě0798443961 | m3 | Stěna | 0 | 0.125 | 1.424 | 1.424 | 0.178 | 0.425 | 0.178 | 0.053 | 3.35
ZDIVO Z CDm | Půdorys 2.NP | ZDIVO Z CDm 0.125 m | 1 | ZDIVO Z CDm | A | 1552HWa0798443970 | m3 | Celá stěna | Stávající | Zednické práce | ZDIVO Z CDm |  | 1552Stě0798443971 | m3 | Stěna | 0 | 0.125 | 2.848 | 2.848 | 0.356 | 0.85 | 0.356 | 0.106 | 3.35
ZDIVO Z CDm | Půdorys 2.NP | ZDIVO Z CDm 0.125 m | 1 | ZDIVO Z CDm | A | 1552HWa0798444089 | m3 | Celá stěna | Stávající | Zednické práce | ZDIVO Z CDm |  | 1552Stě0798444090 | m3 | Stěna | 0 | 0.125 | 3.417 | 3.417 | 0.427 | 1.02 | 0.427 | 0.127 | 3.35
ZDIVO Z CDm | Půdorys 2.NP | ZDIVO Z CDm 0.125 m | 1 | ZDIVO Z CDm | A | 1552HWa0798444108 | m3 | Celá stěna | Stávající | Zednické práce | ZDIVO Z CDm |  | 1552Stě0798444109 | m3 | Stěna | 0 | 0.125 | 14.536 | 13.651 | 1.817 | 4.339 | 1.817 | 0.542 | 3.35
PÓROBETONOVÉ ZDIVO | Půdorys 2.NP | PÓROBETONOVÉ ZDIVO 0.1 m | 1 | PÓROBETONOVÉ ZDIVO | EI 120 | 1552HWa0798444177 | m3 | Celá stěna | Stávající | Zednické práce | PÓROBETONOVÉ ZDIVO |  | 1552Stě0798444178 | m2 | Stěna | 1.111 | 0.1 | 14.07 | 14.07 | 1.407 | 4.2 | 1.407 | 0.42 | 3.35 | Pset_WallCommon - AcousticRating: 37 dB
ZDIVO Z CDm | Půdorys 2.NP | ZDIVO Z CDm 0.125 m | 1 | ZDIVO Z CDm | A | 1552HWa0798444186 | m3 | Celá stěna | Stávající | Zednické práce | ZDIVO Z CDm |  | 1552Stě0798444187 | m3 | Stěna | 0 | 0.125 | 14.07 | 14.07 | 1.759 | 4.2 | 1.759 | 0.525 | 3.35
ZDIVO Z CDm | Půdorys 2.NP | ZDIVO Z CDm 0.125 m | 1 | ZDIVO Z CDm | A | 1552HWa0798444195 | m3 | Celá stěna | Stávající | Zednické práce | ZDIVO Z CDm |  | 1552Stě0798444196 | m3 | Stěna | 0 | 0.125 | 14.74 | 11.609 | 1.842 | 4.4 | 1.451 | 0.55 | 3.35
ZDIVO Z CDm | Půdorys 2.NP | ZDIVO Z CDm 0.125 m | 1 | ZDIVO Z CDm | A | 1552HWa0798444204 | m3 | Celá stěna | Stávající | Zednické práce | ZDIVO Z CDm |  | 1552Stě0798444205 | m3 | Stěna | 0 | 0.125 | 3.199 | 3.199 | 0.4 | 0.955 | 0.4 | 0.119 | 3.35
ZDIVO Z CDm | Půdorys 2.NP | ZDIVO Z CDm 0.125 m | 1 | ZDIVO Z CDm | A | 1552HWa0798444213 | m3 | Celá stěna | Stávající | Zednické práce | ZDIVO Z CDm |  | 1552Stě0798444214 | m3 | Stěna | 0 | 0.125 | 0.921 | 0.921 | 0.115 | 0.275 | 0.115 | 0.034 | 3.35
ZDIVO Z CDm | Půdorys 2.NP | ZDIVO Z CDm 0.125 m | 1 | ZDIVO Z CDm | A | 1552HWa0798444230 | m3 | Celá stěna | Stávající | Zednické práce | ZDIVO Z CDm |  | 1552Stě0798444231 | m3 | Stěna | 0 | 0.125 | 1.34 | 1.34 | 0.167 | 0.4 | 0.167 | 0.05 | 3.35
ZDIVO Z CDm | Půdorys 2.NP | ZDIVO Z CDm 0.125 m | 1 | ZDIVO Z CDm | A | 1552HWa0798444241 | m3 | Celá stěna | Stávající | Zednické práce | ZDIVO Z CDm |  | 1552Stě0798444242 | m3 | Stěna | 0 | 0.125 | 1.759 | 1.759 | 0.22 | 0.525 | 0.22 | 0.066 | 3.35
ZDIVO Z CDm | Půdorys 2.NP | ZDIVO Z CDm 0.125 m | 1 | ZDIVO Z CDm | A | 1552HWa0798444255 | m3 | Celá stěna | Stávající | Zednické práce | ZDIVO Z CDm |  | 1552Stě0798444256 | m3 | Stěna | 0 | 0.125 | 0.921 | 0.921 | 0.115 | 0.275 | 0.115 | 0.034 | 3.35
ZDIVO Z CDm | Půdorys 2.NP | ZDIVO Z CDm 0.125 m | 1 | ZDIVO Z CDm | A | 1552HWa0798444285 | m3 | Celá stěna | Stávající | Zednické práce | ZDIVO Z CDm |  | 1552Stě0798444286 | m3 | Stěna | 0 | 0.125 | 28.224 | 26.204 | 3.528 | 8.425 | 3.275 | 1.053 | 3.35
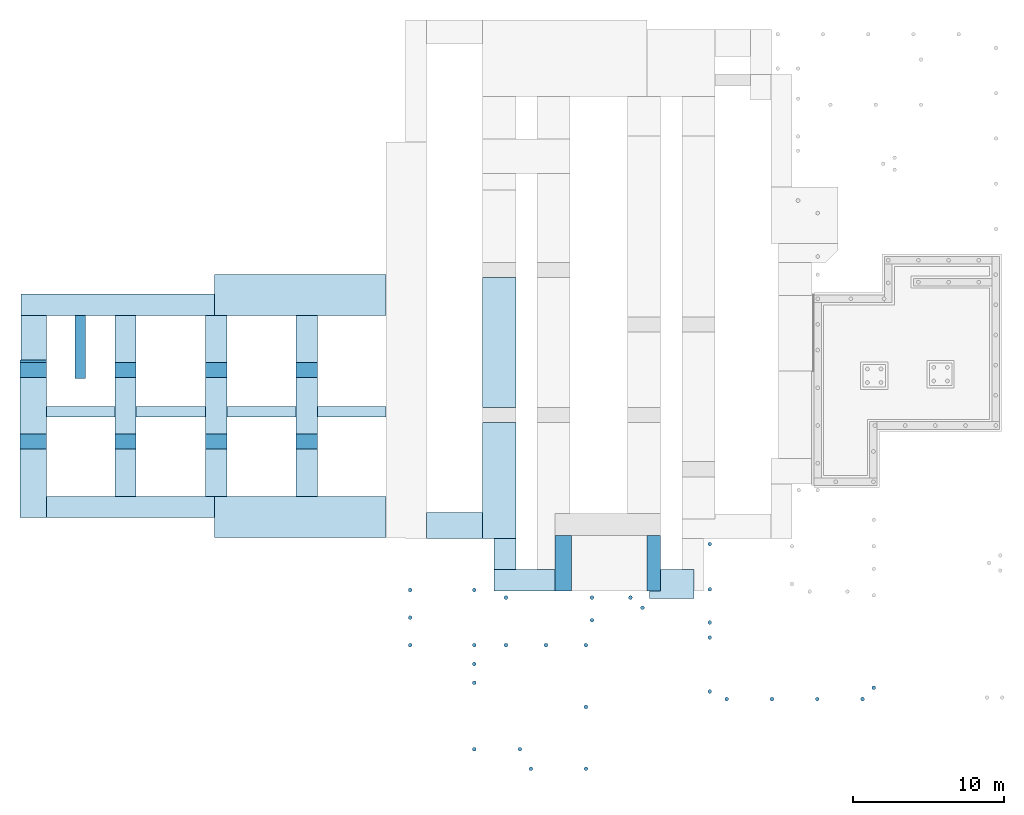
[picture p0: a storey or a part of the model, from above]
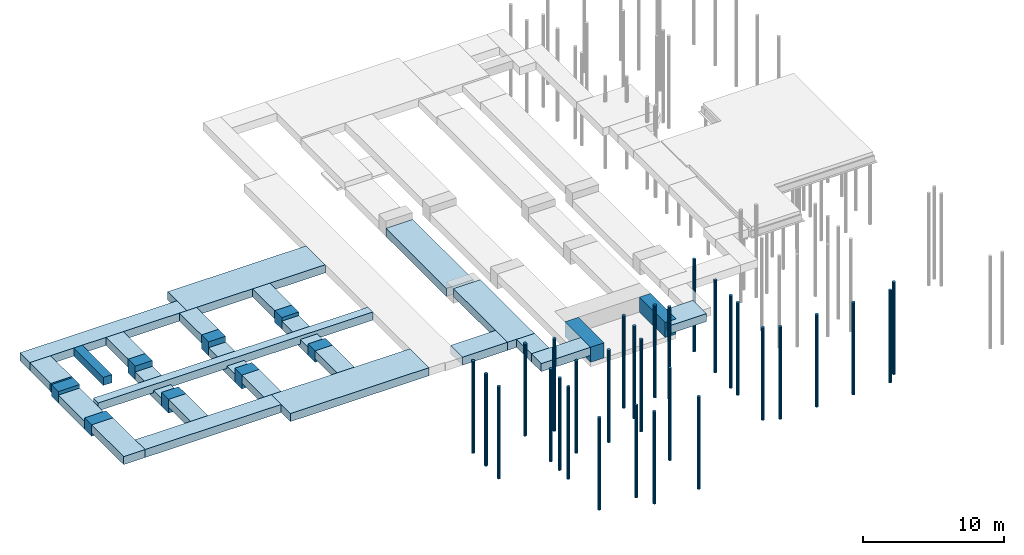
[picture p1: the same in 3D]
Properties of the parts of a building model (IFC4), part 37 of 45

# IfcWall (2385)
Name | In | Material | Faktor | Označení | Požární odolnost | Allright_Stavebni_dil_ID | Jednotka | Název_objektu | Object Layer Attributes #1, Status | Object Layer Attributes #1, Práce | Object Layer Attributes #1, Materiál | Object Layer Attributes #1, Staticky nosná konstrukce | Object Layer Attributes #1, Allright_Stavebni_dil_ID | Object Layer Attributes #1, Jednotka | Object Layer Attributes #1, Název_objektu | ThermalTransmittance (W/K/m2) | Width (m) | GrossSideArea (m2) | NetSideArea (m2) | GrossVolume (m3) | Length (m) | NetVolume (m3) | GrossFootprintArea (m2) | Height (m)
ZDIVO Z CDm | Půdorys 2.NP | ZDIVO Z CDm 0.125 m | 1 | ZDIVO Z CDm | A | 1552HWa0798444307 | m3 | Celá stěna | Stávající | Zednické práce | ZDIVO Z CDm |  | 1552Stě0798444308 | m3 | Stěna | 0 | 0.125 | 0.67 | 0.67 | 0.084 | 0.2 | 0.084 | 0.025 | 3.35
ZDIVO Z CDm | Půdorys 2.NP | ZDIVO Z CDm 0.125 m | 1 | ZDIVO Z CDm | A | 1552HWa0798444319 | m3 | Celá stěna | Stávající | Zednické práce | ZDIVO Z CDm |  | 1552Stě0798444320 | m3 | Stěna | 0 | 0.125 | 4.104 | 4.104 | 0.513 | 1.225 | 0.513 | 0.153 | 3.35
ZDIVO Z CDm | Půdorys 2.NP | ZDIVO Z CDm 0.125 m | 1 | ZDIVO Z CDm | A | 1552HWa0798444331 | m3 | Celá stěna | Stávající | Zednické práce | ZDIVO Z CDm |  | 1552Stě0798444332 | m3 | Stěna | 0 | 0.125 | 2.998 | 2.998 | 0.375 | 0.895 | 0.375 | 0.112 | 3.35
PÓROBETONOVÉ ZDIVO | Půdorys 2.NP | PÓROBETONOVÉ ZDIVO 0.1 m | 1 | PÓROBETONOVÉ ZDIVO | EI 120 | 1552HWa0798444433 | m3 | Celá stěna | Stávající | Zednické práce | PÓROBETONOVÉ ZDIVO |  | 1552Stě0798444434 | m2 | Stěna | 1.111 | 0.1 | 17.185 | 15.368 | 1.719 | 5.13 | 1.537 | 0.513 | 3.35 | Pset_WallCommon - AcousticRating: 37 dB
ZDIVO Z CDm | Půdorys 2.NP | ZDIVO Z CDm 0.2 m | 1 | ZDIVO Z CDm | A | 1552HWa0798444505 | m3 | Celá stěna | Stávající | Zednické práce | ZDIVO Z CDm | no | 1552Stě0798444512 | m3 | Stěna | 0 | 0.2 | 2.01 | 2.01 | 0.402 | 0.6 | 0.402 | 0.12 | 3.35
ZDIVO Z CDm | Půdorys 2.NP | ZDIVO Z CDm 0.125 m | 1 | ZDIVO Z CDm | A | 1552HWa0798444507 | m3 | Celá stěna | Stávající | Zednické práce | ZDIVO Z CDm |  | 1552Stě0798444510 | m3 | Stěna | 0 | 0.125 | 3.35 | 3.35 | 0.419 | 1 | 0.419 | 0.125 | 3.35
PÓROBETONOVÉ ZDIVO | Půdorys 2.NP | PÓROBETONOVÉ ZDIVO 0.1 m | 1 | PÓROBETONOVÉ ZDIVO | EI 120 | 1552HWa0798444533 | m3 | Celá stěna | Stávající | Zednické práce | PÓROBETONOVÉ ZDIVO |  | 1552Stě0798444534 | m2 | Stěna | 1.111 | 0.1 | 21.122 | 21.122 | 2.112 | 6.305 | 2.112 | 0.63 | 3.35 | Pset_WallCommon - AcousticRating: 37 dB
ZDIVO Z CDm | Půdorys 2.NP | ZDIVO Z CDm 0.125 m | 1 | ZDIVO Z CDm | A | 1552HWa0798444273 | m3 | Celá stěna | Stávající | Zednické práce | ZDIVO Z CDm |  | 1552Stě0798444274 | m3 | Stěna | 0 | 0.125 | 28.224 | 26.406 | 3.528 | 8.425 | 3.301 | 1.053 | 3.35
ZDIVO Z CDm | Půdorys 2.NP | ZDIVO Z CDm 0.125 m | 1 | ZDIVO Z CDm | A | 1552HWa0798444350 | m3 | Celá stěna | Stávající | Zednické práce | ZDIVO Z CDm |  | 1552Stě0798444351 | m3 | Stěna | 0 | 0.125 | 1.424 | 1.424 | 0.178 | 0.425 | 0.178 | 0.053 | 3.35
ZDIVO Z CDm | Půdorys 2.NP | ZDIVO Z CDm 0.125 m | 1 | ZDIVO Z CDm | A | 1552HWa0798444372 | m3 | Celá stěna | Stávající | Zednické práce | ZDIVO Z CDm |  | 1552Stě0798444373 | m3 | Stěna | 0 | 0.125 | 1.005 | 1.005 | 0.126 | 0.3 | 0.126 | 0.037 | 3.35
ZDIVO Z CDm | Půdorys 2.NP | ZDIVO Z CDm 0.125 m | 1 | ZDIVO Z CDm | A | 1552HWa0798444360 | m3 | Celá stěna | Stávající | Zednické práce | ZDIVO Z CDm |  | 1552Stě0798444361 | m3 | Stěna | 0 | 0.125 | 5.276 | 5.276 | 0.66 | 1.575 | 0.66 | 0.197 | 3.35
ZDIVO Z CDm | Půdorys 2.NP | ZDIVO Z CDm 0.125 m | 1 | ZDIVO Z CDm | A | 1552HWa0798444758 | m3 | Celá stěna | Stávající | Zednické práce | ZDIVO Z CDm |  | 1552Stě0798444759 | m3 | Stěna | 0 | 0.125 | 2.429 | 2.429 | 0.304 | 0.725 | 0.304 | 0.091 | 3.35
ZDIVO Z CDm | Půdorys 2.NP | ZDIVO Z CDm 0.125 m | 1 | ZDIVO Z CDm | A | 1552HWa0798444767 | m3 | Celá stěna | Stávající | Zednické práce | ZDIVO Z CDm |  | 1552Stě0798444768 | m3 | Stěna | 0 | 0.125 | 3.082 | 3.082 | 0.385 | 0.92 | 0.385 | 0.115 | 3.35
ZDIVO Z CDm | Půdorys 2.NP | ZDIVO Z CDm 0.125 m | 1 | ZDIVO Z CDm | A | 1552HWa0798444784 | m3 | Celá stěna | Stávající | Zednické práce | ZDIVO Z CDm |  | 1552Stě0798444785 | m3 | Stěna | 0 | 0.125 | 1.759 | 1.759 | 0.22 | 0.525 | 0.22 | 0.066 | 3.35
ZDIVO Z CDm | Půdorys 2.NP | ZDIVO Z CDm 0.125 m | 1 | ZDIVO Z CDm | A | 1552HWa0798444794 | m3 | Celá stěna | Stávající | Zednické práce | ZDIVO Z CDm |  | 1552Stě0798444795 | m3 | Stěna | 0 | 0.125 | 3.35 | 3.35 | 0.419 | 1 | 0.419 | 0.125 | 3.35
PÓROBETONOVÉ ZDIVO | Půdorys 2.NP | PÓROBETONOVÉ ZDIVO 0.1 m | 1 | PÓROBETONOVÉ ZDIVO | EI 120 | 1552HWa0798444808 | m3 | Celá stěna | Stávající | Zednické práce | PÓROBETONOVÉ ZDIVO |  | 1552Stě0798444809 | m2 | Stěna | 1.111 | 0.1 | 10.301 | 8.483 | 1.03 | 3.075 | 0.848 | 0.308 | 3.35 | Pset_WallCommon - AcousticRating: 37 dB
PÓROBETONOVÉ ZDIVO | Půdorys 2.NP | PÓROBETONOVÉ ZDIVO 0.1 m | 1 | PÓROBETONOVÉ ZDIVO | EI 120 | 1552HWa0798444820 | m3 | Celá stěna | Stávající | Zednické práce | PÓROBETONOVÉ ZDIVO |  | 1552Stě0798444821 | m2 | Stěna | 1.111 | 0.1 | 8.207 | 7.898 | 0.821 | 2.45 | 0.79 | 0.245 | 3.35 | Pset_WallCommon - AcousticRating: 37 dB
ZDIVO Z CDm | Půdorys 2.NP | ZDIVO Z CDm 0.125 m | 1 | ZDIVO Z CDm | A | 1552HWa0798444912 | m3 | Celá stěna | Stávající | Zednické práce | ZDIVO Z CDm |  | 1552Stě0798444913 | m3 | Stěna | 0 | 0.125 | 3.35 | 3.35 | 0.419 | 1 | 0.419 | 0.125 | 3.35
PLYNOSILIKÁT | Půdorys 2.NP | PLYNOSILIKÁT 0.3 m | 1 | PLYNOSILIKÁT | REI 180 | 1552HWa0798445184 | m3 | Celá stěna | Stávající | Zednické práce | PLYNOSILIKÁT |  | 1552Stě0798445188 | m3 | Stěna | 0.541 | 0.3 | 2.952 | 3.312 | 0.886 | 0.82 | 0.886 | 0.246 | 3.6 | Pset_WallCommon - AcousticRating: 48 dB
PLYNOSILIKÁT | Půdorys 2.NP | PLYNOSILIKÁT 0.3 m | 1 | PLYNOSILIKÁT | REI 180 | 1552HWa0798445244 | m3 | Celá stěna | Stávající | Zednické práce | PLYNOSILIKÁT |  | 1552Stě0798445245 | m3 | Stěna | 0.541 | 0.3 | 1.08 | 1.08 | 0.324 | 0.3 | 0.324 | 0.09 | 3.6 | Pset_WallCommon - AcousticRating: 48 dB
ZELEZOBETONOVÁ KCE | Půdorys 2.NP | ZELEZOBETONOVÁ KCE 0.3 m | 1 | ZELEZOBETONOVÁ KCE | A | 1552HWa0798424758 | m3 | Celá stěna | Stávající | Betonářské práce | ZELEZOBETONOVÁ KCE |  | 1552Stě0798424759 | m3 | Stěna | 0 | 0.3 | 4.32 | 4.32 | 1.296 | 1.2 | 1.296 | 0.36 | 3.6
ZDIVO Z CDm | Půdorys 2.NP | ZDIVO Z CDm | 1 | ZDIVO Z CDm | A | 1552HWa0798446579 | m3 | Celá stěna | Stávající | Zednické práce | ZDIVO Z CDm |  | 1552Stě0798446587 | m3 | Stěna | 0 | 0.3 | 8.19 | 1.988 | 2.457 | 2.275 | 0.451 | 0.682 | 3.6
ZDIVO Z CDm | Půdorys 2.NP | ZDIVO Z CDm 0.125 m | 1 | ZDIVO Z CDm | A | 1552HWa0798447072 | m3 | Celá stěna | Stávající | Zednické práce | ZDIVO Z CDm | yes | 1552Stě0798447134 | m3 | Stěna | 0 | 0.125 | 4.774 | 4.054 | 0.597 | 1.425 | 0.507 | 0.178 | 3.35
ZDIVO Z CDm | Půdorys 2.NP | ZDIVO Z CDm 0.125 m | 1 | ZDIVO Z CDm | A | 1552HWa0798447074 | m3 | Celá stěna | Stávající | Zednické práce | ZDIVO Z CDm | yes | 1552Stě0798447109 | m3 | Stěna | 0 | 0.125 | 11.055 | 11.055 | 1.382 | 3.3 | 1.382 | 0.413 | 3.35
ZDIVO Z CDm | Půdorys 2.NP | ZDIVO Z CDm 0.125 m | 1 | ZDIVO Z CDm | A | 1552HWa0798447075 | m3 | Celá stěna | Stávající | Zednické práce | ZDIVO Z CDm | yes | 1552Stě0798447130 | m3 | Stěna | 0 | 0.125 | 3.517 | 3.518 | 0.44 | 1.05 | 0.44 | 0.131 | 3.35
ZDIVO Z CDm | Půdorys 2.NP | ZDIVO Z CDm 0.25 m | 1 | ZDIVO Z CDm | A | 1552HWa0798447094 | m3 | Celá stěna | Stávající | Zednické práce | ZDIVO Z CDm | yes | 1552Stě0798447128 | m3 | Stěna | 0 | 0.25 | 11.055 | 11.055 | 2.764 | 3.3 | 2.764 | 0.825 | 3.35
ZDIVO Z CDm | Půdorys 2.NP | ZDIVO Z CDm 0.125 m | 1 | ZDIVO Z CDm | A | 1552HWa0798447093 | m3 | Celá stěna | Stávající | Zednické práce | ZDIVO Z CDm | yes | 1552Stě0798447111 | m3 | Stěna | 0 | 0.125 | 3.517 | 2.798 | 0.44 | 1.05 | 0.35 | 0.131 | 3.35
ZELEZOBETONOVÁ KCE | Půdorys 2.NP | ZELEZOBETONOVÁ KCE 0.3 m | 1 | ZELEZOBETONOVÁ KCE | A | 1552HWa0798420431 | m3 | Celá stěna | Stávající | Betonářské práce | ZELEZOBETONOVÁ KCE |  | 1552Stě0798422389 | m3 | Stěna | 0 | 0.3 | 10.8 | 10.8 | 3.24 | 3 | 3.24 | 0.9 | 3.6
ZELEZOBETONOVÁ KCE | Půdorys 2.NP | EPS 0.1 m, ZELEZOBETONOVÁ KCE 0.3 m |  | ZELEZOBETONOVÁ KCE | A | 1552HWa0798420402 | m3 | Celá stěna | Stávající | Zateplovací systémy | EPS | no | 1552Stě0798422374 | m2 | Stěna | 0 | 0.4 | 10.8 | 10.8 | 3.919 | 3.24 | 3.919 | 1.248 | 3.6 | NEMSOK - Object Layer Attributes #2, 2D interakce: yes; Object Layer Attributes #2, Status: Stávající; Object Layer Attributes #2, Práce: Betonářské práce; Object Layer Attributes #2, Materiál: ZELEZOBETONOVÁ KCE; Object Layer Attributes #2, Allright_Stavebni_dil_ID: 1552Stě0798450079; Object Layer Attributes #2, Jednotka: m3; Object Layer Attributes #2, Název_objektu: Stěna; Object Layer Attributes #2, Staticky nosná konstrukce: no
EPS | Půdorys 2.NP | EPS 0.1 m |  | EPS |  | 1552HWa0798447819 | m3 | Celá stěna | Stávající | Zateplovací systémy | EPS | no | 1552Stě0798447822 | m2 | Stěna |  | 0.1 | 8.568 | 8.568 | 0.857 | 2.38 | 0.857 | 0.238 | 3.6
ZELEZOBETONOVÁ KCE | Půdorys 2.NP | EPS 0.15 m, ZELEZOBETONOVÁ KCE 0.3 m | 1 | ZELEZOBETONOVÁ KCE | A | 1552HWa0798450149 | m3 | Celá stěna | Stávající | Zateplovací systémy | EPS | no | 1552Stě0798450171 | m2 | Stěna | 0 | 0.45 | 28.8 | 28.8 | 10.98 | 8 | 10.98 | 3.6 | 3.6 | NEMSOK - Object Layer Attributes #2, 2D interakce: yes; Object Layer Attributes #2, Status: Stávající; Object Layer Attributes #2, Práce: Betonářské práce; Object Layer Attributes #2, Materiál: ZELEZOBETONOVÁ KCE; Object Layer Attributes #2, Allright_Stavebni_dil_ID: 1552Stě0798450170; Object Layer Attributes #2, Jednotka: m3; Object Layer Attributes #2, Název_objektu: Stěna; Object Layer Attributes #2, Staticky nosná konstrukce: no
ZELEZOBETONOVÁ KCE | Půdorys 2.NP | EPS 0.1 m, ZELEZOBETONOVÁ KCE 0.3 m | 1 | ZELEZOBETONOVÁ KCE | A | 1552HWa0798450499 | m3 | Celá stěna | Stávající | Zateplovací systémy | EPS | no | 1552Stě0798450511 | m2 | Stěna | 0 | 0.4 | 9.72 | 6.72 | 3.462 | 2.75 | 2.337 | 1.09 | 3.6 | NEMSOK - Object Layer Attributes #2, 2D interakce: yes; Object Layer Attributes #2, Status: Stávající; Object Layer Attributes #2, Práce: Betonářské práce; Object Layer Attributes #2, Materiál: ZELEZOBETONOVÁ KCE; Object Layer Attributes #2, Allright_Stavebni_dil_ID: 1552Stě0798450510; Object Layer Attributes #2, Jednotka: m3; Object Layer Attributes #2, Název_objektu: Stěna; Object Layer Attributes #2, Staticky nosná konstrukce: no
ZDIVO Z CDm | Půdorys 2.NP | ZDIVO Z CDm 0.5 m | 1 | ZDIVO Z CDm | A | 1552HWa0798450889 | m3 | Celá stěna | Stávající | Zednické práce | ZDIVO Z CDm | yes | 1552Stě0798450897 | m3 | Stěna | 0 | 0.5 | 15.097 | 9.716 | 7.549 | 4.95 | 4.858 | 2.475 | 3.05
ZDIVO Z CDm | Půdorys 2.NP | EPS 0.1 m, ZDIVO Z CDm 0.5 m |  | ZDIVO Z CDm | A | 1552HWa0000000008 | m3 | Celá stěna | Stávající | Zateplovací systémy | EPS | no | 1552Stě0000001502 | m2 | Stěna | 0 | 0.6 | 23.76 | 23.76 | 13.966 | 7.4 | 13.966 | 4.52 | 3.3 | NEMSOK - Object Layer Attributes #2, 2D interakce: yes; Object Layer Attributes #2, Status: Stávající; Object Layer Attributes #2, Práce: Zednické práce; Object Layer Attributes #2, Materiál: ZDIVO Z CDm; Object Layer Attributes #2, Allright_Stavebni_dil_ID: 1552Stě0798450796; Object Layer Attributes #2, Jednotka: m3; Object Layer Attributes #2, Název_objektu: Stěna; Object Layer Attributes #2, Staticky nosná konstrukce: yes
ZDIVO Z CDm | Půdorys 2.NP | EPS 0.1 m, ZDIVO Z CDm 0.5 m |  | ZDIVO Z CDm | A | 1552HWa0000000016 | m3 | Celá stěna | Stávající | Zateplovací systémy | EPS | no | 1552Stě0000001508 | m2 | Stěna | 0 | 0.6 | 28.215 | 28.215 | 15.098 | 8.3 | 15.098 | 4.88 | 3.3 | NEMSOK - Object Layer Attributes #2, 2D interakce: yes; Object Layer Attributes #2, Status: Stávající; Object Layer Attributes #2, Práce: Zednické práce; Object Layer Attributes #2, Materiál: ZDIVO Z CDm; Object Layer Attributes #2, Allright_Stavebni_dil_ID: 1552Stě0798450844; Object Layer Attributes #2, Jednotka: m3; Object Layer Attributes #2, Název_objektu: Stěna; Object Layer Attributes #2, Staticky nosná konstrukce: yes
ZDIVO Z CDm | Půdorys 2.NP | EPS 0.1 m, ZDIVO Z CDm 0.5 m |  | ZDIVO Z CDm | A | 1552HWa0798451081 | m3 | Celá stěna | Stávající | Zateplovací systémy | EPS | no | 1552Stě0798451082 | m2 | Stěna | 0 | 0.6 | 2.31 | 2.31 | 0.689 | 0.5 | 0.689 | 0.22 | 3.3 | NEMSOK - Object Layer Attributes #2, 2D interakce: yes; Object Layer Attributes #2, Status: Stávající; Object Layer Attributes #2, Práce: Zednické práce; Object Layer Attributes #2, Materiál: ZDIVO Z CDm; Object Layer Attributes #2, Allright_Stavebni_dil_ID: 1552Stě0798451083; Object Layer Attributes #2, Jednotka: m3; Object Layer Attributes #2, Název_objektu: Stěna; Object Layer Attributes #2, Staticky nosná konstrukce: yes
ZDIVO Z CDm | Půdorys 2.NP | EPS 0.1 m, ZDIVO Z CDm 0.5 m |  | ZDIVO Z CDm | A | 1552HWa0000000006 | m3 | Celá stěna | Stávající | Zateplovací systémy | EPS | no | 1552Stě0000001506 | m2 | Stěna | 0 | 0.6 | 11.88 | 11.88 | 6.373 | 3.5 | 6.373 | 2.06 | 3.3 | NEMSOK - Object Layer Attributes #2, 2D interakce: yes; Object Layer Attributes #2, Status: Stávající; Object Layer Attributes #2, Práce: Zednické práce; Object Layer Attributes #2, Materiál: ZDIVO Z CDm; Object Layer Attributes #2, Allright_Stavebni_dil_ID: 1552Stě0798450966; Object Layer Attributes #2, Jednotka: m3; Object Layer Attributes #2, Název_objektu: Stěna; Object Layer Attributes #2, Staticky nosná konstrukce: yes
ZDIVO Z CDm | Půdorys 2.NP | EPS 0.1 m, ZDIVO Z CDm 0.5 m |  | ZDIVO Z CDm | A | 1552HWa0000000004 | m3 | Celá stěna | Stávající | Zateplovací systémy | EPS | no | 1552Stě0000001491 | m2 | Stěna | 0 | 0.6 | 30.855 | 30.855 | 15.819 | 8.85 | 15.819 | 5.11 | 3.3 | NEMSOK - Object Layer Attributes #2, 2D interakce: yes; Object Layer Attributes #2, Status: Stávající; Object Layer Attributes #2, Práce: Zednické práce; Object Layer Attributes #2, Materiál: ZDIVO Z CDm; Object Layer Attributes #2, Allright_Stavebni_dil_ID: 1552Stě0798451123; Object Layer Attributes #2, Jednotka: m3; Object Layer Attributes #2, Název_objektu: Stěna; Object Layer Attributes #2, Staticky nosná konstrukce: yes
STÁVAJÍCÍ KCE | Půdorys 2.NP | STÁVAJÍC KCE 0.4 m | 1 | STÁVAJÍCÍ KCE | REI 180 | 1552HWa0798447632 | m3 | Celá stěna | Stávající | Zednické práce | STÁVAJÍC KCE |  | 1552Stě0798447643 | m3 | Stěna | 0.541 | 0.4 | 2.09 | 2.045 | 0.836 | 1.9 | 0.818 | 0.76 | 1.1 | Pset_WallCommon - AcousticRating: 48 dB
STÁVAJÍCÍ KCE | Půdorys 2.NP | STÁVAJÍC KCE 0.4 m | 1 | STÁVAJÍCÍ KCE | REI 180 | 1552HWa0798447633 | m3 | Celá stěna | Stávající | Zednické práce | STÁVAJÍC KCE |  | 1552Stě0798447645 | m3 | Stěna | 0.541 | 0.4 | 4.125 | 4.125 | 1.65 | 3.75 | 1.65 | 1.5 | 1.1 | Pset_WallCommon - AcousticRating: 48 dB
STÁVAJÍCÍ KCE | Půdorys 2.NP | STÁVAJÍC KCE 0.4 m | 1 | STÁVAJÍCÍ KCE | REI 180 | 1552HWa0798447635 | m3 | Celá stěna | Stávající | Zednické práce | STÁVAJÍC KCE |  | 1552Stě0798447640 | m3 | Stěna | 0.541 | 0.4 | 10.34 | 10.182 | 4.136 | 9.4 | 4.073 | 3.76 | 1.1 | Pset_WallCommon - AcousticRating: 48 dB
STÁVAJÍCÍ KCE | Půdorys 2.NP | STÁVAJÍC KCE 0.4 m | 1 | STÁVAJÍCÍ KCE | REI 180 | 1552HWa0798447602 | m3 | Celá stěna | Stávající | Zednické práce | STÁVAJÍC KCE |  | 1552Stě0798447603 | m3 | Stěna | 0.541 | 0.4 | 3.52 | 3.52 | 1.408 | 3.2 | 1.408 | 1.28 | 1.1 | Pset_WallCommon - AcousticRating: 48 dB
STÁVAJÍCÍ KCE | Půdorys 2.NP | STÁVAJÍC KCE 0.4 m | 1 | STÁVAJÍCÍ KCE | REI 180 | 1552HWa0798447327 | m3 | Celá stěna | Stávající | Zednické práce | STÁVAJÍC KCE |  | 1552Stě0798447328 | m3 | Stěna | 0.541 | 0.4 | 7.645 | 7.645 | 3.058 | 6.95 | 3.058 | 2.78 | 1.1 | Pset_WallCommon - AcousticRating: 48 dB
STÁVAJÍCÍ KCE | Půdorys 2.NP | STÁVAJÍC KCE 0.4 m |  | STÁVAJÍCÍ KCE | REI 180 | 1552HWa0798447638 | m3 | Celá stěna | Stávající | Zednické práce | STÁVAJÍC KCE |  | 1552Stě0798447648 | m3 | Stěna | 0.541 | 0.4 | 2.09 | 2.09 | 0.836 | 1.9 | 0.836 | 0.76 | 1.1 | Pset_WallCommon - AcousticRating: 48 dB
ZELEZOBETONOVÁ KCE | Půdorys 2.NP | EPS 0.1 m, ZELEZOBETONOVÁ KCE 0.3 m | 1 | ZELEZOBETONOVÁ KCE | A | 1552HWa0798420407 | m3 | Celá stěna | Stávající | Zateplovací systémy | EPS | no | 1552Stě0798422449 | m2 | Stěna | 0 | 0.4 | 11.88 | 8.73 | 4.207 | 3.3 | 3.165 | 1.32 | 3.6 | NEMSOK - Object Layer Attributes #2, 2D interakce: yes; Object Layer Attributes #2, Status: Stávající; Object Layer Attributes #2, Práce: Betonářské práce; Object Layer Attributes #2, Materiál: ZELEZOBETONOVÁ KCE; Object Layer Attributes #2, Allright_Stavebni_dil_ID: 1552Stě0798448324; Object Layer Attributes #2, Jednotka: m3; Object Layer Attributes #2, Název_objektu: Stěna; Object Layer Attributes #2, Staticky nosná konstrukce: no
EPS | Půdorys 2.NP | EPS 0.1 m |  | EPS |  | 1552HWa0798448025 | m3 | Celá stěna | Stávající | Zateplovací systémy | EPS | no | 1552Stě0798448026 | m2 | Stěna |  | 0.1 | 2.34 | 2.34 | 0.234 | 1.2 | 0.234 | 0.12 | 1.95
ZELEZOBETONOVÁ KCE | Půdorys 2.NP | EPS 0.1 m, ZELEZOBETONOVÁ KCE 0.3 m | 1 | ZELEZOBETONOVÁ KCE | A | 1552HWa0798419876 | m3 | Celá stěna | Stávající | Zateplovací systémy | EPS |  | 1552Stě0798419877 | m2 | Stěna | 0 | 0.4 | 29.88 | 29.88 | 11.916 | 8.25 | 11.916 | 3.31 | 3.6 | NEMSOK - Object Layer Attributes #2, 2D interakce: yes; Object Layer Attributes #2, Status: Stávající; Object Layer Attributes #2, Práce: Betonářské práce; Object Layer Attributes #2, Materiál: ZELEZOBETONOVÁ KCE; Object Layer Attributes #2, Allright_Stavebni_dil_ID: 1552Stě0798444949; Object Layer Attributes #2, Jednotka: m3; Object Layer Attributes #2, Název_objektu: Stěna
ZDIVO Z CDm | Půdorys 2.NP | EPS 0.1 m, ZDIVO Z CDm 0.3 m |  | ZDIVO Z CDm | A | 1552HWa0798424649 | m3 | Celá stěna | Stávající | Zateplovací systémy | EPS | no | 1552Stě0798424650 | m2 | Stěna | 0 | 0.4 | 2.178 | 2.178 | 0.849 | 0.805 | 0.849 | 0.282 | 3.6 | NEMSOK - Object Layer Attributes #2, 2D interakce: yes; Object Layer Attributes #2, Status: Stávající; Object Layer Attributes #2, Práce: Zednické práce; Object Layer Attributes #2, Materiál: ZDIVO Z CDm; Object Layer Attributes #2, Allright_Stavebni_dil_ID: 1552Stě0798445923; Object Layer Attributes #2, Jednotka: m3; Object Layer Attributes #2, Název_objektu: Stěna; Object Layer Attributes #2, Staticky nosná konstrukce: no
ZDIVO Z CDm | Půdorys 2.NP | ZDIVO Z CDm 0.125 m | 1 | ZDIVO Z CDm | A | 1552HWa0798452015 | m3 | Celá stěna | Stávající | Zednické práce | ZDIVO Z CDm |  | 1552Stě0798452016 | m3 | Stěna | 0 | 0.125 | 0.67 | 0.67 | 0.084 | 0.2 | 0.084 | 0.025 | 3.35
PÓROBETONOVÉ ZDIVO | Půdorys 2.NP | PÓROBETONOVÉ ZDIVO 0.1 m | 1 | PÓROBETONOVÉ ZDIVO | EI 120 | 1552HWa0798453453 | m3 | Celá stěna | Stávající | Zednické práce | PÓROBETONOVÉ ZDIVO |  | 1552Stě0798453454 | m2 | Stěna | 1.111 | 0.1 | 31.323 | 29.303 | 3.132 | 9.35 | 2.93 | 0.935 | 3.35 | Pset_WallCommon - AcousticRating: 37 dB
PÓROBETONOVÉ ZDIVO | Půdorys 2.NP | PÓROBETONOVÉ ZDIVO 0.1 m | 1 | PÓROBETONOVÉ ZDIVO | EI 120 | 1552HWa0798454022 | m3 | Celá stěna | Stávající | Zednické práce | PÓROBETONOVÉ ZDIVO |  | 1552Stě0798454023 | m2 | Stěna | 1.111 | 0.1 | 13.165 | 13.166 | 1.317 | 3.93 | 1.317 | 0.393 | 3.35 | Pset_WallCommon - AcousticRating: 37 dB
PÓROBETONOVÉ ZDIVO | Půdorys 2.NP | PÓROBETONOVÉ ZDIVO 0.1 m | 1 | PÓROBETONOVÉ ZDIVO | EI 120 | 1552HWa0798453577 | m3 | Celá stěna | Stávající | Zednické práce | PÓROBETONOVÉ ZDIVO |  | 1552Stě0798453578 | m2 | Stěna | 1.111 | 0.1 | 7.119 | 5.301 | 0.712 | 2.125 | 0.53 | 0.212 | 3.35 | Pset_WallCommon - AcousticRating: 37 dB
ZDIVO Z CDm | Půdorys 2.NP | ZDIVO Z CDm 0.125 m | 1 | ZDIVO Z CDm | A | 1552HWa0798454099 | m3 | Celá stěna | Stávající | Zednické práce | ZDIVO Z CDm | yes | 1552Stě0798454100 | m3 | Stěna | 0 | 0.125 | 1.675 | 1.675 | 0.209 | 0.5 | 0.209 | 0.063 | 3.35
ZDIVO Z CDm | Půdorys 2.NP | ZDIVO Z CDm 0.125 m | 1 | ZDIVO Z CDm | A | 1552HWa0798454148 | m3 | Celá stěna | Stávající | Zednické práce | ZDIVO Z CDm |  | 1552Stě0798454149 | m3 | Stěna | 0 | 0.125 | 5.025 | 5.025 | 0.628 | 1.5 | 0.628 | 0.187 | 3.35
ZDIVO Z CDm | Půdorys 2.NP | ZDIVO Z CDm 0.125 m | 1 | ZDIVO Z CDm | A | 1552HWa0798454157 | m3 | Celá stěna | Stávající | Zednické práce | ZDIVO Z CDm |  | 1552Stě0798454158 | m3 | Stěna | 0 | 0.125 | 1.759 | 1.759 | 0.22 | 0.525 | 0.22 | 0.066 | 3.35
ZDIVO Z CDm | Půdorys 2.NP | ZDIVO Z CDm 0.125 m | 1 | ZDIVO Z CDm | A | 1552HWa0798454164 | m3 | Celá stěna | Stávající | Zednické práce | ZDIVO Z CDm |  | 1552Stě0798454165 | m3 | Stěna | 0 | 0.125 | 1.591 | 1.591 | 0.199 | 0.475 | 0.199 | 0.059 | 3.35
ZDIVO Z CDm | Půdorys 2.NP | ZDIVO Z CDm 0.125 m | 1 | ZDIVO Z CDm | A | 1552HWa0798454204 | m3 | Celá stěna | Stávající | Zednické práce | ZDIVO Z CDm |  | 1552Stě0798454206 | m3 | Stěna | 0 | 0.125 | 5.796 | 5.796 | 0.724 | 1.73 | 0.724 | 0.216 | 3.35
ZDIVO Z CDm | Půdorys 2.NP | ZDIVO Z CDm 0.125 m | 1 | ZDIVO Z CDm | A | 1552HWa0798454214 | m3 | Celá stěna | Stávající | Zednické práce | ZDIVO Z CDm |  | 1552Stě0798454215 | m3 | Stěna | 0 | 0.125 | 5.025 | 5.025 | 0.628 | 1.5 | 0.628 | 0.188 | 3.35
ZDIVO Z CDm | Půdorys 2.NP | ZDIVO Z CDm 0.125 m | 1 | ZDIVO Z CDm | A | 1552HWa0798454221 | m3 | Celá stěna | Stávající | Zednické práce | ZDIVO Z CDm |  | 1552Stě0798454222 | m3 | Stěna | 0 | 0.125 | 3.116 | 3.116 | 0.389 | 0.93 | 0.389 | 0.116 | 3.35
ZDIVO Z CDm | Půdorys 2.NP | ZDIVO Z CDm 0.125 m | 1 | ZDIVO Z CDm | A | 1552HWa0798454235 | m3 | Celá stěna | Stávající | Zednické práce | ZDIVO Z CDm |  | 1552Stě0798454236 | m3 | Stěna | 0 | 0.125 | 5.025 | 5.025 | 0.628 | 1.5 | 0.628 | 0.188 | 3.35
ZDIVO Z CDm | Půdorys 2.NP | ZDIVO Z CDm 0.125 m | 1 | ZDIVO Z CDm | A | 1552HWa0798454242 | m3 | Celá stěna | Stávající | Zednické práce | ZDIVO Z CDm |  | 1552Stě0798454243 | m3 | Stěna | 0 | 0.125 | 3.116 | 3.116 | 0.389 | 0.93 | 0.389 | 0.116 | 3.35
ZDIVO Z CDm | Půdorys 2.NP | ZDIVO Z CDm 0.125 m | 1 | ZDIVO Z CDm | A | 1552HWa0798454256 | m3 | Celá stěna | Stávající | Zednické práce | ZDIVO Z CDm |  | 1552Stě0798454257 | m3 | Stěna | 0 | 0.125 | 5.796 | 5.796 | 0.724 | 1.73 | 0.724 | 0.216 | 3.35
ZDIVO Z CDm | Půdorys 2.NP | ZDIVO Z CDm 0.125 m | 1 | ZDIVO Z CDm | A | 1552HWa0798454265 | m3 | Celá stěna | Stávající | Zednické práce | ZDIVO Z CDm |  | 1552Stě0798454266 | m3 | Stěna | 0 | 0.125 | 1.759 | 1.759 | 0.22 | 0.525 | 0.22 | 0.066 | 3.35
ZDIVO Z CDm | Půdorys 2.NP | ZDIVO Z CDm 0.125 m | 1 | ZDIVO Z CDm | A | 1552HWa0798454275 | m3 | Celá stěna | Stávající | Zednické práce | ZDIVO Z CDm |  | 1552Stě0798454276 | m3 | Stěna | 0 | 0.125 | 3.116 | 3.116 | 0.389 | 0.93 | 0.389 | 0.116 | 3.35
ZDIVO Z CDm | Půdorys 2.NP | ZDIVO Z CDm 0.125 m | 1 | ZDIVO Z CDm | A | 1552HWa0798454291 | m3 | Celá stěna | Stávající | Zednické práce | ZDIVO Z CDm |  | 1552Stě0798454293 | m3 | Stěna | 0 | 0.125 | 5.796 | 5.796 | 0.724 | 1.73 | 0.724 | 0.216 | 3.35
ZDIVO Z CDm | Půdorys 2.NP | ZDIVO Z CDm 0.125 m | 1 | ZDIVO Z CDm | A | 1552HWa0798454300 | m3 | Celá stěna | Stávající | Zednické práce | ZDIVO Z CDm |  | 1552Stě0798454301 | m3 | Stěna | 0 | 0.125 | 10.151 | 10.151 | 1.269 | 3.03 | 1.269 | 0.379 | 3.35
 | Půdorys 2.NP | ZELEZOBETONOVÁ KCE 0.5 m | 1 |  |  | 1554HWa0000000007 | m3 | Celá stěna | Stávající | Betonářské práce | ZELEZOBETONOVÁ KCE | yes | 1554Ven0000000052 | m2 | Věnec |  | 0.5 | 0.75 | 0.75 | 0.375 | 0 | 0.375 | 1.5 | 0.25
 | Půdorys 2.NP | ZELEZOBETONOVÁ KCE 0.5 m |  |  |  | 1554HWa0000000011 | m3 | Celá stěna | Stávající | Betonářské práce | ZELEZOBETONOVÁ KCE | yes | 1554Ven0000000066 | m2 | Věnec |  | 0.5 | 1.888 | 1.888 | 0.944 | 0 | 0.944 | 3.775 | 0.25
 | Půdorys 2.NP | ZELEZOBETONOVÁ KCE 0.5 m |  |  |  | 1554HWa0000000038 | m3 | Celá stěna | Stávající | Betonářské práce | ZELEZOBETONOVÁ KCE | yes | 1554Ven0000000054 | m2 | Věnec |  | 0.5 | 1.888 | 1.888 | 0.944 | 0 | 0.944 | 3.775 | 0.25
EPS | Půdorys 2.NP | EPS 0.1 m |  | EPS |  | 1554HWa0000000864 | m3 | Celá stěna | Stávající | Zateplovací systémy | EPS | no | 1554Stě0000000870 | m2 | Stěna |  | 0.1 | 0.55 | 0.55 | 0.055 | 2.2 | 0.055 | 0.22 | 0.25
EPS | Půdorys 2.NP | EPS 0.1 m |  | EPS |  | 1554HWa0000000868 | m3 | Celá stěna | Stávající | Zateplovací systémy | EPS | no | 1554Stě0000000874 | m2 | Stěna |  | 0.1 | 1.15 | 1.15 | 0.115 | 4.6 | 0.115 | 0.46 | 0.25
EPS | Půdorys 2.NP | EPS 0.1 m |  | EPS |  | 1554HWa0000000871 | m3 | Celá stěna | Stávající | Zateplovací systémy | EPS | no | 1554Stě0000000879 | m2 | Stěna |  | 0.1 | 1.15 | 1.15 | 0.115 | 4.6 | 0.115 | 0.46 | 0.25
 | Půdorys 2.NP | ZELEZOBETONOVÁ KCE 0.45 m, LIGNOPOR 0.05 m |  |  |  | 1554HWa0000000008 | m3 | Celá stěna | Stávající | Betonářské práce | ZELEZOBETONOVÁ KCE | yes | 1554Ven0000000062 | m2 | Věnec |  | 0.5 | 2.325 | 2.325 | 1.106 | 0 | 1.106 | 4.425 | 0.25 | NEMSOK - Object Layer Attributes #2, 2D interakce: yes; Object Layer Attributes #2, Status: Stávající; Object Layer Attributes #2, Práce: Zateplovací systémy; Object Layer Attributes #2, Materiál: LIGNOPOR; Object Layer Attributes #2, Allright_Stavebni_dil_ID: 1554Ven0000000016; Object Layer Attributes #2, Jednotka: m2; Object Layer Attributes #2, Název_objektu: Věnec; Object Layer Attributes #2, Staticky nosná konstrukce: no
 | Půdorys 2.NP | ZELEZOBETONOVÁ KCE 0.45 m, LIGNOPOR 0.05 m |  |  |  | 1554HWa0000000002 | m3 | Celá stěna | Stávající | Betonářské práce | ZELEZOBETONOVÁ KCE | yes | 1554Ven0000000064 | m2 | Věnec |  | 0.5 | 0.837 | 0.838 | 0.362 | 0 | 0.362 | 1.45 | 0.25 | NEMSOK - Object Layer Attributes #2, 2D interakce: yes; Object Layer Attributes #2, Status: Stávající; Object Layer Attributes #2, Práce: Zateplovací systémy; Object Layer Attributes #2, Materiál: LIGNOPOR; Object Layer Attributes #2, Allright_Stavebni_dil_ID: 1554Ven0000000013; Object Layer Attributes #2, Jednotka: m2; Object Layer Attributes #2, Název_objektu: Věnec; Object Layer Attributes #2, Staticky nosná konstrukce: no
 | Půdorys 2.NP | ZELEZOBETONOVÁ KCE 0.45 m, LIGNOPOR 0.05 m |  |  |  | 1554HWa0000000004 | m3 | Celá stěna | Stávající | Betonářské práce | ZELEZOBETONOVÁ KCE | yes | 1554Ven0000000060 | m2 | Věnec |  | 0.5 | 0.188 | 0.188 | 0.049 | 0 | 0.049 | 0.195 | 0.25 | NEMSOK - Object Layer Attributes #2, 2D interakce: yes; Object Layer Attributes #2, Status: Stávající; Object Layer Attributes #2, Práce: Zateplovací systémy; Object Layer Attributes #2, Materiál: LIGNOPOR; Object Layer Attributes #2, Allright_Stavebni_dil_ID: 1554Ven0000000019; Object Layer Attributes #2, Jednotka: m2; Object Layer Attributes #2, Název_objektu: Věnec; Object Layer Attributes #2, Staticky nosná konstrukce: no
 | Půdorys 2.NP | ZELEZOBETONOVÁ KCE 0.45 m, LIGNOPOR 0.05 m |  |  |  | 1554HWa0000000005 | m3 | Celá stěna | Stávající | Betonářské práce | ZELEZOBETONOVÁ KCE | yes | 1554Ven0000000068 | m2 | Věnec |  | 0.5 | 0.875 | 0.875 | 0.432 | 0 | 0.432 | 1.727 | 0.25 | NEMSOK - Object Layer Attributes #2, 2D interakce: yes; Object Layer Attributes #2, Status: Stávající; Object Layer Attributes #2, Práce: Zateplovací systémy; Object Layer Attributes #2, Materiál: LIGNOPOR; Object Layer Attributes #2, Allright_Stavebni_dil_ID: 1554Ven0000000023; Object Layer Attributes #2, Jednotka: m2; Object Layer Attributes #2, Název_objektu: Věnec; Object Layer Attributes #2, Staticky nosná konstrukce: no
 | Půdorys 2.NP | ZELEZOBETONOVÁ KCE 0.45 m, LIGNOPOR 0.05 m |  |  |  | 1554HWa0000000020 | m3 | Celá stěna | Stávající | Betonářské práce | ZELEZOBETONOVÁ KCE | yes | 1554Ven0000000045 | m2 | Věnec |  | 0.5 | 1.012 | 1.013 | 0.456 | 0 | 0.456 | 1.822 | 0.25 | NEMSOK - Object Layer Attributes #2, 2D interakce: yes; Object Layer Attributes #2, Status: Stávající; Object Layer Attributes #2, Práce: Zateplovací systémy; Object Layer Attributes #2, Materiál: LIGNOPOR; Object Layer Attributes #2, Allright_Stavebni_dil_ID: 1554Ven0000000027; Object Layer Attributes #2, Jednotka: m2; Object Layer Attributes #2, Název_objektu: Věnec; Object Layer Attributes #2, Staticky nosná konstrukce: no
 | Půdorys 2.NP | ZELEZOBETONOVÁ KCE 0.45 m, LIGNOPOR 0.05 m |  |  |  | 1554HWa0000000024 | m3 | Celá stěna | Stávající | Betonářské práce | ZELEZOBETONOVÁ KCE | yes | 1554Ven0000000035 | m2 | Věnec |  | 0.5 | 2.138 | 2.138 | 1.058 | 0 | 1.058 | 4.23 | 0.25 | NEMSOK - Object Layer Attributes #2, 2D interakce: yes; Object Layer Attributes #2, Status: Stávající; Object Layer Attributes #2, Práce: Zateplovací systémy; Object Layer Attributes #2, Materiál: LIGNOPOR; Object Layer Attributes #2, Allright_Stavebni_dil_ID: 1554Ven0000000033; Object Layer Attributes #2, Jednotka: m2; Object Layer Attributes #2, Název_objektu: Věnec; Object Layer Attributes #2, Staticky nosná konstrukce: no
 | Půdorys 2.NP | ZELEZOBETONOVÁ KCE 0.45 m, LIGNOPOR 0.05 m |  |  |  | 1554HWa0000000028 | m3 | Celá stěna | Stávající | Betonářské práce | ZELEZOBETONOVÁ KCE | yes | 1554Ven0000000056 | m2 | Věnec |  | 0.5 | 1.012 | 1.013 | 0.456 | 0 | 0.456 | 1.822 | 0.25 | NEMSOK - Object Layer Attributes #2, 2D interakce: yes; Object Layer Attributes #2, Status: Stávající; Object Layer Attributes #2, Práce: Zateplovací systémy; Object Layer Attributes #2, Materiál: LIGNOPOR; Object Layer Attributes #2, Allright_Stavebni_dil_ID: 1554Ven0000000031; Object Layer Attributes #2, Jednotka: m2; Object Layer Attributes #2, Název_objektu: Věnec; Object Layer Attributes #2, Staticky nosná konstrukce: no
 | Půdorys 2.NP | ZELEZOBETONOVÁ KCE 0.45 m, LIGNOPOR 0.05 m |  |  |  | 1554HWa0000000010 | m3 | Celá stěna | Stávající | Betonářské práce | ZELEZOBETONOVÁ KCE | yes | 1554Ven0000000070 | m2 | Věnec |  | 0.5 | 1.6 | 1.6 | 0.794 | 0 | 0.794 | 3.178 | 0.25 | NEMSOK - Object Layer Attributes #2, 2D interakce: yes; Object Layer Attributes #2, Status: Stávající; Object Layer Attributes #2, Práce: Zateplovací systémy; Object Layer Attributes #2, Materiál: LIGNOPOR; Object Layer Attributes #2, Allright_Stavebni_dil_ID: 1554Ven0000000037; Object Layer Attributes #2, Jednotka: m2; Object Layer Attributes #2, Název_objektu: Věnec; Object Layer Attributes #2, Staticky nosná konstrukce: no
OBKLAD SKLEM | Půdorys 2.NP | OBKLAD SKLEM 0.01 m |  | OBKLAD SKLEM |  | 1564HWa0798476186 | m3 | Celá stěna | Nový | Sklenářské práce | OBKLAD SKLEM |  | 1564Stě0798476189 | m2 | Stěna | 0 | 0.01 | 57.061 | 57.061 | 0.571 | 44.93 | 0.571 | 0.449 | 1.27 | NEMSOK - Object Layer Attributes #1, Kód prvku: OD03.04.0002; Object Layer Attributes #1, Podlaží: 2.NP; Object Layer Attributes #1, Způsob položení: kotveno bodově
OBKLAD SKLEM | Půdorys 2.NP | OBKLAD SKLEM 0.01 m |  | OBKLAD SKLEM |  | 1564HWa0798476184 | m3 | Celá stěna | Nový | Sklenářské práce | OBKLAD SKLEM |  | 1564Stě0798476191 | m2 | Stěna | 0 | 0.01 | 25.108 | 25.108 | 0.251 | 19.77 | 0.251 | 0.198 | 1.27 | NEMSOK - Object Layer Attributes #1, Kód prvku: OD03.04.0001; Object Layer Attributes #1, Podlaží: 2.NP; Object Layer Attributes #1, Způsob položení: kotveno bodově
YTONG 300 | Půdorys 2.NP | YTONG 300 0.3 m |  | YTONG 300 | REI 180 | 1564HWa0798463246 | m3 | Celá stěna | Nový | Zednické práce | YTONG 300 | no | 1564Stě0798463247 | m3 | Stěna | 0.541 | 0.3 | 6.281 | 3.131 | 1.884 | 1.875 | 0.939 | 0.563 | 3.35 | Pset_WallCommon - AcousticRating: 48 dB; NEMSOK - Object Layer Attributes #1, Kód prvku: SN06.04.1001; Object Layer Attributes #1, Funkce: Ano; Object Layer Attributes #1, U-hodnota: 0.362; Object Layer Attributes #1, Podlaží: 2.NP; Object Layer Attributes #1, Neprůzvučnost: 44 dB; Object Layer Attributes #1, Požární odolnost: REI 180; Object Layer Attributes #1, Pevnost zdiva: 2,32 N/mm2; Object Layer Attributes #1, Funkce (venkovní): Ano; Object Layer Attributes #1, Statická funkce: Ne
YTONG 300 | Půdorys 2.NP | YTONG 300 0.3 m |  | YTONG 300 | REI 180 | 1564HWa0000002706 | m3 | Celá stěna | Nový | Zednické práce | YTONG 300 | no | 1564Stě0000002707 | m3 | Stěna | 0.541 | 0.3 | 10.34 | 10.34 | 3.102 | 9.4 | 3.102 | 2.82 | 1.1 | Pset_WallCommon - AcousticRating: 48 dB; NEMSOK - Object Layer Attributes #1, Kód prvku: SN06.04.2003; Object Layer Attributes #1, Funkce: Ano; Object Layer Attributes #1, U-hodnota: 0.362; Object Layer Attributes #1, Podlaží: 2.NP; Object Layer Attributes #1, Neprůzvučnost: 44 dB; Object Layer Attributes #1, Požární odolnost: REI 180; Object Layer Attributes #1, Pevnost zdiva: 2,32 N/mm2; Object Layer Attributes #1, Funkce (venkovní): Ano; Object Layer Attributes #1, Statická funkce: Ne
YTONG 300 | Půdorys 2.NP | YTONG 300 0.3 m |  | YTONG 300 | REI 180 | 1564HWa0000001201 | m3 | Celá stěna | Nový | Zednické práce | YTONG 300 | no | 1564Stě0000001202 | m3 | Stěna | 0.541 | 0.3 | 3 | 3 | 0.9 | 1.5 | 0.9 | 0.45 | 2 | Pset_WallCommon - AcousticRating: 48 dB; NEMSOK - Object Layer Attributes #1, Kód prvku: SN06.04.2001; Object Layer Attributes #1, Funkce: Ano; Object Layer Attributes #1, U-hodnota: 0.362; Object Layer Attributes #1, Podlaží: 2.NP; Object Layer Attributes #1, Neprůzvučnost: 44 dB; Object Layer Attributes #1, Požární odolnost: REI 180; Object Layer Attributes #1, Pevnost zdiva: 2,32 N/mm2; Object Layer Attributes #1, Funkce (venkovní): Ano; Object Layer Attributes #1, Statická funkce: Ne
YTONG 300 | Půdorys 2.NP | YTONG 300 0.3 m |  | YTONG 300 | REI 180 | 1564HWa0000002699 | m3 | Celá stěna | Nový | Zednické práce | YTONG 300 | no | 1564Stě0000002700 | m3 | Stěna | 0.541 | 0.3 | 1.1 | 1.1 | 0.33 | 1 | 0.33 | 0.3 | 1.1 | Pset_WallCommon - AcousticRating: 48 dB; NEMSOK - Object Layer Attributes #1, Kód prvku: SN06.04.2002; Object Layer Attributes #1, Funkce: Ano; Object Layer Attributes #1, U-hodnota: 0.362; Object Layer Attributes #1, Podlaží: 2.NP; Object Layer Attributes #1, Neprůzvučnost: 44 dB; Object Layer Attributes #1, Požární odolnost: REI 180; Object Layer Attributes #1, Pevnost zdiva: 2,32 N/mm2; Object Layer Attributes #1, Funkce (venkovní): Ano; Object Layer Attributes #1, Statická funkce: Ne
YTONG 300 | Půdorys 2.NP | YTONG 300 0.3 m |  | YTONG 300 | REI 180 | 1564HWa0798463228 | m3 | Celá stěna | Nový | Zednické práce | YTONG 300 | no | 1564Stě0798463229 | m3 | Stěna | 0.541 | 0.3 | 1.1 | 1.1 | 0.33 | 1 | 0.33 | 0.3 | 1.1 | Pset_WallCommon - AcousticRating: 48 dB; NEMSOK - Object Layer Attributes #1, Kód prvku: SN06.04.1002; Object Layer Attributes #1, Funkce: Ano; Object Layer Attributes #1, U-hodnota: 0.362; Object Layer Attributes #1, Podlaží: 2.NP; Object Layer Attributes #1, Neprůzvučnost: 44 dB; Object Layer Attributes #1, Požární odolnost: REI 180; Object Layer Attributes #1, Pevnost zdiva: 2,32 N/mm2; Object Layer Attributes #1, Funkce (venkovní): Ano; Object Layer Attributes #1, Statická funkce: Ne
YTONG 300 | Půdorys 2.NP | YTONG 300 0.3 m |  | YTONG 300 | REI 180 | 1564HWa0798468833 | m3 | Celá stěna | Nový | Zednické práce | YTONG 300 | no | 1564Stě0798468834 | m3 | Stěna | 0.541 | 0.3 | 5.936 | 0 | 1.781 | 2.8 | 0 | 0.84 | 2.12 | Pset_WallCommon - AcousticRating: 48 dB; NEMSOK - Object Layer Attributes #1, Kód prvku: SN06.04.1003; Object Layer Attributes #1, Funkce: Ano; Object Layer Attributes #1, U-hodnota: 0.362; Object Layer Attributes #1, Podlaží: 2.NP; Object Layer Attributes #1, Neprůzvučnost: 44 dB; Object Layer Attributes #1, Požární odolnost: REI 180; Object Layer Attributes #1, Pevnost zdiva: 2,32 N/mm2; Object Layer Attributes #1, Funkce (venkovní): Ano; Object Layer Attributes #1, Statická funkce: Ne
MINERÁLNÍ VATA | Půdorys 2.NP | ZELEZOBETONOVÁ KCE 0.25 m, MINERÁLNÍ VATA 0.3 m |  | MINERÁLNÍ VATA |  | 1564HWa0798464296 | m3 | Celá stěna | Nový | Betonářské práce | ZELEZOBETONOVÁ KCE | yes | 1564Stě0798464297 | m3 | Stěna |  | 0.55 | 5.124 | 2.804 | 2.517 | 1.85 | 1.181 | 1.03 | 2.45 | NEMSOK - Object Layer Attributes #2, 2D interakce: yes; Object Layer Attributes #2, Status: Nový; Object Layer Attributes #2, Práce: Zateplovací systémy; Object Layer Attributes #2, Materiál: MINERÁLNÍ VATA; Object Layer Attributes #2, Allright_Stavebni_dil_ID: 1564Stě0798464298; Object Layer Attributes #2, Jednotka: m3; Object Layer Attributes #2, Název_objektu: Stěna; Object Layer Attributes #2, Staticky nosná konstrukce: no; Object Layer Attributes #1, Kód prvku: SN02.04.0003; Object Layer Attributes #1, Funkce: Ano; Object Layer Attributes #1, U-hodnota: 0; Object Layer Attributes #1, Podlaží: 2.NP; Object Layer Attributes #1, Požární odolnost: A; Object Layer Attributes #1, Třída pevnosti ocele: B500B; Object Layer Attributes #1, Stupeň vyztužení: 150; Object Layer Attributes #1, Třída pevnosti betonu: C25/30-XC1; Object Layer Attributes #1, Krytí výztuže: 25mm; Object Layer Attributes #1, Statická funkce: Ano; Object Layer Attributes #2, Kód prvku: TI06.04.0009; Object Layer Attributes #2, Požární odolnost: A1; Object Layer Attributes #2, Součinitel prostupu tepla: 0.036; Object Layer Attributes #2, Součinitel difúzního odporu: 1; Object Layer Attributes #2, Způsob spojení vrstev: Lepený + mechanicky kotvený; Object Layer Attributes #2, Systém kotvení: -
MINERÁLNÍ VATA | Půdorys 2.NP | ZELEZOBETONOVÁ KCE 0.25 m, MINERÁLNÍ VATA 0.3 m |  | MINERÁLNÍ VATA |  | 1564HWa0798466541 | m3 | Celá stěna | Nový | Betonářské práce | ZELEZOBETONOVÁ KCE | yes | 1564Stě0798466543 | m3 | Stěna |  | 0.55 | 4.685 | 4.566 | 2.385 | 1.76 | 2.35 | 0.976 | 2.45 | NEMSOK - Object Layer Attributes #2, 2D interakce: yes; Object Layer Attributes #2, Status: Nový; Object Layer Attributes #2, Práce: Zateplovací systémy; Object Layer Attributes #2, Materiál: MINERÁLNÍ VATA; Object Layer Attributes #2, Allright_Stavebni_dil_ID: 1564Stě0798466544; Object Layer Attributes #2, Jednotka: m3; Object Layer Attributes #2, Název_objektu: Stěna; Object Layer Attributes #2, Staticky nosná konstrukce: no; Object Layer Attributes #1, Kód prvku: SN02.04.0004; Object Layer Attributes #1, Funkce: Ano; Object Layer Attributes #1, U-hodnota: 0; Object Layer Attributes #1, Podlaží: 2.NP; Object Layer Attributes #1, Požární odolnost: A; Object Layer Attributes #1, Třída pevnosti ocele: B500B; Object Layer Attributes #1, Stupeň vyztužení: 150; Object Layer Attributes #1, Třída pevnosti betonu: C25/30-XC1; Object Layer Attributes #1, Krytí výztuže: 25mm; Object Layer Attributes #1, Statická funkce: Ano; Object Layer Attributes #2, Kód prvku: TI06.04.0010; Object Layer Attributes #2, Požární odolnost: A1; Object Layer Attributes #2, Součinitel prostupu tepla: 0.036; Object Layer Attributes #2, Součinitel difúzního odporu: 1; Object Layer Attributes #2, Způsob spojení vrstev: Lepený + mechanicky kotvený; Object Layer Attributes #2, Systém kotvení: -
MINERÁLNÍ VATA | Půdorys 2.NP | ZELEZOBETONOVÁ KCE |  | MINERÁLNÍ VATA |  | 1564HWa0798464283 | m3 | Celá stěna | Nový | Betonářské práce | ZELEZOBETONOVÁ KCE | yes | 1564Stě0798464284 | m3 | Stěna |  | 0.55 | 4.685 | 4.514 | 2.385 | 1.76 | 2.332 | 0.976 | 2.45 | NEMSOK - Object Layer Attributes #2, 2D interakce: yes; Object Layer Attributes #2, Status: Nový; Object Layer Attributes #2, Práce: Zateplovací systémy; Object Layer Attributes #2, Materiál: MINERÁLNÍ VATA; Object Layer Attributes #2, Allright_Stavebni_dil_ID: 1564Stě0798464285; Object Layer Attributes #2, Jednotka: m3; Object Layer Attributes #2, Název_objektu: Stěna; Object Layer Attributes #2, Staticky nosná konstrukce: no; Object Layer Attributes #1, Kód prvku: SN02.04.0002; Object Layer Attributes #1, Funkce: Ano; Object Layer Attributes #1, U-hodnota: 0; Object Layer Attributes #1, Podlaží: 2.NP; Object Layer Attributes #1, Požární odolnost: A; Object Layer Attributes #1, Třída pevnosti ocele: B500B; Object Layer Attributes #1, Stupeň vyztužení: 150; Object Layer Attributes #1, Třída pevnosti betonu: C25/30-XC1; Object Layer Attributes #1, Krytí výztuže: 25mm; Object Layer Attributes #1, Statická funkce: Ano; Object Layer Attributes #2, Kód prvku: TI06.04.0008; Object Layer Attributes #2, Požární odolnost: A1; Object Layer Attributes #2, Součinitel prostupu tepla: 0.036; Object Layer Attributes #2, Součinitel difúzního odporu: 1; Object Layer Attributes #2, Způsob spojení vrstev: Lepený + mechanicky kotvený; Object Layer Attributes #2, Systém kotvení: -
MINERÁLNÍ VATA | Půdorys 2.NP | MINERÁLNÍ VATA 0.3 m, ZELEZOBETONOVÁ KCE 0.2 m, MINERÁLNÍ VATA 0.16 m |  | MINERÁLNÍ VATA |  | 1564HWa0000000081 | m3 | Celá stěna | Nový | Zateplovací systémy | MINERÁLNÍ VATA | no | 1564Stě0000000082 | m3 | Stěna |  | 0.66 | 7.644 | 7.644 | 4.044 | 5.427 | 4.044 | 3.643 | 1.3 | NEMSOK - Object Layer Attributes #2, 2D interakce: yes; Object Layer Attributes #2, Status: Nový; Object Layer Attributes #2, Práce: Betonářské práce; Object Layer Attributes #2, Materiál: ZELEZOBETONOVÁ KCE; Object Layer Attributes #2, Allright_Stavebni_dil_ID: 1564Stě0000000083; Object Layer Attributes #2, Jednotka: m3; Object Layer Attributes #2, Název_objektu: Stěna; Object Layer Attributes #3, 2D interakce: yes; Object Layer Attributes #3, Status: Nový; Object Layer Attributes #3, Práce: Zateplovací systémy; Object Layer Attributes #3, Materiál: MINERÁLNÍ VATA; Object Layer Attributes #3, Allright_Stavebni_dil_ID: 1564Stě0000000084; Object Layer Attributes #3, Jednotka: m3; Object Layer Attributes #3, Název_objektu: Stěna; Object Layer Attributes #2, Staticky nosná konstrukce: yes; Object Layer Attributes #3, Staticky nosná konstrukce: no; Object Layer Attributes #1, Kód prvku: TI06.04.0001; Object Layer Attributes #1, Požární odolnost: A1; Object Layer Attributes #1, Systém kotvení: -; Object Layer Attributes #1, Součinitel prostupu tepla: 0.036; Object Layer Attributes #1, Součinitel difúzního odporu: 1; Object Layer Attributes #1, Způsob spojení vrstev: Lepený + mechanicky kotvený; Object Layer Attributes #2, Kód prvku: TM02.04.0001; Object Layer Attributes #2, U-hodnota: 0; Object Layer Attributes #2, Požární odolnost: A; Object Layer Attributes #2, Třída pevnosti ocele: B500B; Object Layer Attributes #2, Funkce: Ano; Object Layer Attributes #2, Stupeň vyztužení: 120; Object Layer Attributes #2, Podlaží: 2.NP; Object Layer Attributes #2, Třída pevnosti betonu: C25/30-XC1; Object Layer Attributes #2, Krytí výztuže: 25mm; Object Layer Attributes #2, Statická funkce: Ano; Object Layer Attributes #3, Kód prvku: TI06.04.1001; Object Layer Attributes #3, Požární odolnost: A1; Object Layer Attributes #3, Systém kotvení: -; Object Layer Attributes #3, Součinitel prostupu tepla: 0.036; Object Layer Attributes #3, Součinitel difúzního odporu: 1; Object Layer Attributes #3, Způsob spojení vrstev: Lepený + mechanicky kotvený
MINERÁLNÍ VATA | Půdorys 2.NP | MINERÁLNÍ VATA 0.3 m, ZELEZOBETONOVÁ KCE 0.2 m, MINERÁLNÍ VATA 0.16 m |  | MINERÁLNÍ VATA |  | 1564HWa0000000284 | m3 | Celá stěna | Nový | Zateplovací systémy | MINERÁLNÍ VATA | no | 1564Stě0000000285 | m3 | Stěna |  | 0.66 | 5.395 | 5.395 | 2.791 | 3.697 | 2.791 | 2.501 | 1.3 | NEMSOK - Object Layer Attributes #2, 2D interakce: yes; Object Layer Attributes #2, Status: Nový; Object Layer Attributes #2, Práce: Betonářské práce; Object Layer Attributes #2, Materiál: ZELEZOBETONOVÁ KCE; Object Layer Attributes #2, Allright_Stavebni_dil_ID: 1564Stě0000000286; Object Layer Attributes #2, Jednotka: m3; Object Layer Attributes #2, Název_objektu: Stěna; Object Layer Attributes #3, 2D interakce: yes; Object Layer Attributes #3, Status: Nový; Object Layer Attributes #3, Práce: Zateplovací systémy; Object Layer Attributes #3, Materiál: MINERÁLNÍ VATA; Object Layer Attributes #3, Allright_Stavebni_dil_ID: 1564Stě0000000287; Object Layer Attributes #3, Jednotka: m3; Object Layer Attributes #3, Název_objektu: Stěna; Object Layer Attributes #2, Staticky nosná konstrukce: yes; Object Layer Attributes #3, Staticky nosná konstrukce: no; Object Layer Attributes #1, Kód prvku: TI06.04.0002; Object Layer Attributes #1, Požární odolnost: A1; Object Layer Attributes #1, Systém kotvení: -; Object Layer Attributes #1, Součinitel prostupu tepla: 0.036; Object Layer Attributes #1, Součinitel difúzního odporu: 1; Object Layer Attributes #1, Způsob spojení vrstev: Lepený + mechanicky kotvený; Object Layer Attributes #2, Kód prvku: TM02.04.0002; Object Layer Attributes #2, U-hodnota: 0; Object Layer Attributes #2, Požární odolnost: A; Object Layer Attributes #2, Třída pevnosti ocele: B500B; Object Layer Attributes #2, Funkce: Ano; Object Layer Attributes #2, Stupeň vyztužení: 120; Object Layer Attributes #2, Podlaží: 2.NP; Object Layer Attributes #2, Třída pevnosti betonu: C25/30-XC1; Object Layer Attributes #2, Krytí výztuže: 25mm; Object Layer Attributes #2, Statická funkce: Ano; Object Layer Attributes #3, Kód prvku: TI06.04.1002; Object Layer Attributes #3, Požární odolnost: A1; Object Layer Attributes #3, Systém kotvení: -; Object Layer Attributes #3, Součinitel prostupu tepla: 0.036; Object Layer Attributes #3, Součinitel difúzního odporu: 1; Object Layer Attributes #3, Způsob spojení vrstev: Lepený + mechanicky kotvený
MINERÁLNÍ VATA | Půdorys 2.NP | MINERÁLNÍ VATA 0.3 m, ZELEZOBETONOVÁ KCE 0.2 m, MINERÁLNÍ VATA 0.16 m |  | MINERÁLNÍ VATA |  | 1564HWa0000000310 | m3 | Celá stěna | Nový | Zateplovací systémy | MINERÁLNÍ VATA | no | 1564Stě0000000311 | m3 | Stěna |  | 0.66 | 5.525 | 5.525 | 3.079 | 4.25 | 3.079 | 2.805 | 1.3 | NEMSOK - Object Layer Attributes #2, 2D interakce: yes; Object Layer Attributes #2, Status: Nový; Object Layer Attributes #2, Práce: Betonářské práce; Object Layer Attributes #2, Materiál: ZELEZOBETONOVÁ KCE; Object Layer Attributes #2, Allright_Stavebni_dil_ID: 1564Stě0000000312; Object Layer Attributes #2, Jednotka: m3; Object Layer Attributes #2, Název_objektu: Stěna; Object Layer Attributes #3, 2D interakce: yes; Object Layer Attributes #3, Status: Nový; Object Layer Attributes #3, Práce: Zateplovací systémy; Object Layer Attributes #3, Materiál: MINERÁLNÍ VATA; Object Layer Attributes #3, Allright_Stavebni_dil_ID: 1564Stě0000000313; Object Layer Attributes #3, Jednotka: m3; Object Layer Attributes #3, Název_objektu: Stěna; Object Layer Attributes #2, Staticky nosná konstrukce: yes; Object Layer Attributes #3, Staticky nosná konstrukce: no; Object Layer Attributes #1, Kód prvku: TI06.04.0003; Object Layer Attributes #1, Požární odolnost: A1; Object Layer Attributes #1, Systém kotvení: -; Object Layer Attributes #1, Součinitel prostupu tepla: 0.036; Object Layer Attributes #1, Součinitel difúzního odporu: 1; Object Layer Attributes #1, Způsob spojení vrstev: Lepený + mechanicky kotvený; Object Layer Attributes #2, Kód prvku: TM02.04.0003; Object Layer Attributes #2, U-hodnota: 0; Object Layer Attributes #2, Požární odolnost: A; Object Layer Attributes #2, Třída pevnosti ocele: B500B; Object Layer Attributes #2, Funkce: Ano; Object Layer Attributes #2, Stupeň vyztužení: 120; Object Layer Attributes #2, Podlaží: 2.NP; Object Layer Attributes #2, Třída pevnosti betonu: C25/30-XC1; Object Layer Attributes #2, Krytí výztuže: 25mm; Object Layer Attributes #2, Statická funkce: Ano; Object Layer Attributes #3, Kód prvku: TI06.04.1003; Object Layer Attributes #3, Požární odolnost: A1; Object Layer Attributes #3, Systém kotvení: -; Object Layer Attributes #3, Součinitel prostupu tepla: 0.036; Object Layer Attributes #3, Součinitel difúzního odporu: 1; Object Layer Attributes #3, Způsob spojení vrstev: Lepený + mechanicky kotvený
MINERÁLNÍ VATA | Půdorys 2.NP | MINERÁLNÍ VATA 0.3 m, ZELEZOBETONOVÁ KCE 0.2 m, MINERÁLNÍ VATA 0.16 m |  | MINERÁLNÍ VATA |  | 1564HWa0000000344 | m3 | Celá stěna | Nový | Zateplovací systémy | MINERÁLNÍ VATA | no | 1564Stě0000000345 | m3 | Stěna |  | 0.66 | 8.963 | 8.964 | 4.995 | 6.895 | 4.995 | 4.551 | 1.3 | NEMSOK - Object Layer Attributes #2, 2D interakce: yes; Object Layer Attributes #2, Status: Nový; Object Layer Attributes #2, Práce: Betonářské práce; Object Layer Attributes #2, Materiál: ZELEZOBETONOVÁ KCE; Object Layer Attributes #2, Allright_Stavebni_dil_ID: 1564Stě0000000346; Object Layer Attributes #2, Jednotka: m3; Object Layer Attributes #2, Název_objektu: Stěna; Object Layer Attributes #3, 2D interakce: yes; Object Layer Attributes #3, Status: Nový; Object Layer Attributes #3, Práce: Zateplovací systémy; Object Layer Attributes #3, Materiál: MINERÁLNÍ VATA; Object Layer Attributes #3, Allright_Stavebni_dil_ID: 1564Stě0000000347; Object Layer Attributes #3, Jednotka: m3; Object Layer Attributes #3, Název_objektu: Stěna; Object Layer Attributes #2, Staticky nosná konstrukce: yes; Object Layer Attributes #3, Staticky nosná konstrukce: no; Object Layer Attributes #1, Kód prvku: TI06.04.0004; Object Layer Attributes #1, Požární odolnost: A1; Object Layer Attributes #1, Systém kotvení: -; Object Layer Attributes #1, Součinitel prostupu tepla: 0.036; Object Layer Attributes #1, Součinitel difúzního odporu: 1; Object Layer Attributes #1, Způsob spojení vrstev: Lepený + mechanicky kotvený; Object Layer Attributes #2, Kód prvku: TM02.04.0004; Object Layer Attributes #2, U-hodnota: 0; Object Layer Attributes #2, Požární odolnost: A; Object Layer Attributes #2, Třída pevnosti ocele: B500B; Object Layer Attributes #2, Funkce: Ano; Object Layer Attributes #2, Stupeň vyztužení: 120; Object Layer Attributes #2, Podlaží: 2.NP; Object Layer Attributes #2, Třída pevnosti betonu: C25/30-XC1; Object Layer Attributes #2, Krytí výztuže: 25mm; Object Layer Attributes #2, Statická funkce: Ano; Object Layer Attributes #3, Kód prvku: TI06.04.1004; Object Layer Attributes #3, Požární odolnost: A1; Object Layer Attributes #3, Systém kotvení: -; Object Layer Attributes #3, Součinitel prostupu tepla: 0.036; Object Layer Attributes #3, Součinitel difúzního odporu: 1; Object Layer Attributes #3, Způsob spojení vrstev: Lepený + mechanicky kotvený
MINERÁLNÍ VATA | Půdorys 2.NP | EPS 0.3 m, ZELEZOBETONOVÁ KCE 0.2 m, MINERÁLNÍ VATA 0.16 m |  | MINERÁLNÍ VATA |  | 1564HWa0000000373 | m3 | Celá stěna | Nový | Zateplovací systémy | EPS | no | 1564Stě0000000374 | m3 | Stěna |  | 0.66 | 3.575 | 3.575 | 1.904 | 2.563 | 1.904 | 1.717 | 1.3 | NEMSOK - Object Layer Attributes #2, 2D interakce: yes; Object Layer Attributes #2, Status: Nový; Object Layer Attributes #2, Práce: Betonářské práce; Object Layer Attributes #2, Materiál: ZELEZOBETONOVÁ KCE; Object Layer Attributes #2, Allright_Stavebni_dil_ID: 1564Stě0000000375; Object Layer Attributes #2, Jednotka: m3; Object Layer Attributes #2, Název_objektu: Stěna; Object Layer Attributes #3, 2D interakce: yes; Object Layer Attributes #3, Status: Nový; Object Layer Attributes #3, Práce: Zateplovací systémy; Object Layer Attributes #3, Materiál: MINERÁLNÍ VATA; Object Layer Attributes #3, Allright_Stavebni_dil_ID: 1564Stě0000000376; Object Layer Attributes #3, Jednotka: m3; Object Layer Attributes #3, Název_objektu: Stěna; Object Layer Attributes #2, Staticky nosná konstrukce: yes; Object Layer Attributes #3, Staticky nosná konstrukce: no; Object Layer Attributes #1, Kód prvku: TI01.04.1001; Object Layer Attributes #1, Požární odolnost: E; Object Layer Attributes #1, Systém kotvení: -; Object Layer Attributes #1, Součinitel prostupu tepla: 0.039; Object Layer Attributes #1, Součinitel difúzního odporu: 20 - 40; Object Layer Attributes #1, Způsob spojení vrstev: Mechanicky kotvený; Object Layer Attributes #2, Kód prvku: TM02.04.0005; Object Layer Attributes #2, U-hodnota: 0; Object Layer Attributes #2, Požární odolnost: A; Object Layer Attributes #2, Třída pevnosti ocele: B500B; Object Layer Attributes #2, Funkce: Ano; Object Layer Attributes #2, Stupeň vyztužení: 120; Object Layer Attributes #2, Podlaží: 2.NP; Object Layer Attributes #2, Třída pevnosti betonu: C25/30-XC1; Object Layer Attributes #2, Krytí výztuže: 25mm; Object Layer Attributes #2, Statická funkce: Ano; Object Layer Attributes #3, Kód prvku: TI06.04.1005; Object Layer Attributes #3, Požární odolnost: A1; Object Layer Attributes #3, Systém kotvení: -; Object Layer Attributes #3, Součinitel prostupu tepla: 0.036; Object Layer Attributes #3, Součinitel difúzního odporu: 1; Object Layer Attributes #3, Způsob spojení vrstev: Lepený + mechanicky kotvený
MINERÁLNÍ VATA | Půdorys 2.NP | EPS 0.25 m, ZELEZOBETONOVÁ KCE 0.2 m, MINERÁLNÍ VATA 0.16 m |  | MINERÁLNÍ VATA |  | 1564HWa0000000665 | m3 | Celá stěna | Nový | Zateplovací systémy | EPS | no | 1564Stě0000000669 | m3 | Stěna |  | 0.61 | 0.975 | 0.975 | 0.59 | 0.95 | 0.59 | 0.562 | 1.3 | NEMSOK - Object Layer Attributes #2, 2D interakce: yes; Object Layer Attributes #2, Status: Nový; Object Layer Attributes #2, Práce: Betonářské práce; Object Layer Attributes #2, Materiál: ZELEZOBETONOVÁ KCE; Object Layer Attributes #2, Allright_Stavebni_dil_ID: 1564Stě0000000668; Object Layer Attributes #2, Jednotka: m3; Object Layer Attributes #2, Název_objektu: Stěna; Object Layer Attributes #3, 2D interakce: yes; Object Layer Attributes #3, Status: Nový; Object Layer Attributes #3, Práce: Zateplovací systémy; Object Layer Attributes #3, Materiál: MINERÁLNÍ VATA; Object Layer Attributes #3, Allright_Stavebni_dil_ID: 1564Stě0000000667; Object Layer Attributes #3, Jednotka: m3; Object Layer Attributes #3, Název_objektu: Stěna; Object Layer Attributes #2, Staticky nosná konstrukce: yes; Object Layer Attributes #3, Staticky nosná konstrukce: no; Object Layer Attributes #1, Kód prvku: TI01.04.1002; Object Layer Attributes #1, Požární odolnost: E; Object Layer Attributes #1, Systém kotvení: -; Object Layer Attributes #1, Součinitel prostupu tepla: 0.039; Object Layer Attributes #1, Součinitel difúzního odporu: 20 - 40; Object Layer Attributes #1, Způsob spojení vrstev: Mechanicky kotvený; Object Layer Attributes #2, Kód prvku: TM02.04.0006; Object Layer Attributes #2, U-hodnota: 0; Object Layer Attributes #2, Požární odolnost: A; Object Layer Attributes #2, Třída pevnosti ocele: B500B; Object Layer Attributes #2, Funkce: Ano; Object Layer Attributes #2, Stupeň vyztužení: 120; Object Layer Attributes #2, Podlaží: 2.NP; Object Layer Attributes #2, Třída pevnosti betonu: C25/30-XC1; Object Layer Attributes #2, Krytí výztuže: 25mm; Object Layer Attributes #2, Statická funkce: Ano; Object Layer Attributes #3, Kód prvku: TI06.04.1006; Object Layer Attributes #3, Požární odolnost: A1; Object Layer Attributes #3, Systém kotvení: -; Object Layer Attributes #3, Součinitel prostupu tepla: 0.036; Object Layer Attributes #3, Součinitel difúzního odporu: 1; Object Layer Attributes #3, Způsob spojení vrstev: Lepený + mechanicky kotvený
MINERÁLNÍ VATA | Půdorys 2.NP | EPS |  | MINERÁLNÍ VATA |  | 1564HWa0000000850 | m3 | Celá stěna | Nový | Zateplovací systémy | EPS | no | 1564Stě0000000851 | m3 | Stěna |  | 0.56 | 0.949 | 0.949 | 0.434 | 0.73 | 0.397 | 0.409 | 1.3 | NEMSOK - Object Layer Attributes #2, 2D interakce: yes; Object Layer Attributes #2, Status: Nový; Object Layer Attributes #2, Práce: Betonářské práce; Object Layer Attributes #2, Materiál: ZELEZOBETONOVÁ KCE; Object Layer Attributes #2, Allright_Stavebni_dil_ID: 1564Stě0000000852; Object Layer Attributes #2, Jednotka: m3; Object Layer Attributes #2, Název_objektu: Stěna; Object Layer Attributes #3, 2D interakce: yes; Object Layer Attributes #3, Status: Nový; Object Layer Attributes #3, Práce: Zateplovací systémy; Object Layer Attributes #3, Materiál: MINERÁLNÍ VATA; Object Layer Attributes #3, Allright_Stavebni_dil_ID: 1564Stě0000000853; Object Layer Attributes #3, Jednotka: m3; Object Layer Attributes #3, Název_objektu: Stěna; Object Layer Attributes #2, Staticky nosná konstrukce: yes; Object Layer Attributes #3, Staticky nosná konstrukce: no; Object Layer Attributes #1, Kód prvku: TI01.04.1003; Object Layer Attributes #1, Požární odolnost: E; Object Layer Attributes #1, Systém kotvení: -; Object Layer Attributes #1, Součinitel prostupu tepla: 0.039; Object Layer Attributes #1, Součinitel difúzního odporu: 20 - 40; Object Layer Attributes #1, Způsob spojení vrstev: Mechanicky kotvený; Object Layer Attributes #2, Kód prvku: TM02.04.0007; Object Layer Attributes #2, U-hodnota: 0; Object Layer Attributes #2, Požární odolnost: A; Object Layer Attributes #2, Třída pevnosti ocele: B500B; Object Layer Attributes #2, Funkce: Ano; Object Layer Attributes #2, Stupeň vyztužení: 120; Object Layer Attributes #2, Podlaží: 2.NP; Object Layer Attributes #2, Třída pevnosti betonu: C25/30-XC1; Object Layer Attributes #2, Krytí výztuže: 25mm; Object Layer Attributes #2, Statická funkce: Ano; Object Layer Attributes #3, Kód prvku: TI06.04.1007; Object Layer Attributes #3, Požární odolnost: A1; Object Layer Attributes #3, Systém kotvení: -; Object Layer Attributes #3, Součinitel prostupu tepla: 0.036; Object Layer Attributes #3, Součinitel difúzního odporu: 1; Object Layer Attributes #3, Způsob spojení vrstev: Lepený + mechanicky kotvený
MINERÁLNÍ VATA | Půdorys 2.NP | EPS |  | MINERÁLNÍ VATA |  | 1564HWa0000000983 | m3 | Celá stěna | Nový | Zateplovací systémy | EPS | no | 1564Stě0000000984 | m3 | Stěna |  | 0.38 | 1.95 | 1.95 | 0.429 | 1.28 | 0.422 | 0.45 | 1.3 | NEMSOK - Object Layer Attributes #2, 2D interakce: yes; Object Layer Attributes #2, Status: Nový; Object Layer Attributes #2, Práce: Betonářské práce; Object Layer Attributes #2, Materiál: ZELEZOBETONOVÁ KCE; Object Layer Attributes #2, Allright_Stavebni_dil_ID: 1564Stě0000000985; Object Layer Attributes #2, Jednotka: m3; Object Layer Attributes #2, Název_objektu: Stěna; Object Layer Attributes #3, 2D interakce: yes; Object Layer Attributes #3, Status: Nový; Object Layer Attributes #3, Práce: Zateplovací systémy; Object Layer Attributes #3, Materiál: MINERÁLNÍ VATA; Object Layer Attributes #3, Allright_Stavebni_dil_ID: 1564Stě0000000986; Object Layer Attributes #3, Jednotka: m3; Object Layer Attributes #3, Název_objektu: Stěna; Object Layer Attributes #2, Staticky nosná konstrukce: yes; Object Layer Attributes #3, Staticky nosná konstrukce: no; Object Layer Attributes #1, Kód prvku: TI01.04.1004; Object Layer Attributes #1, Požární odolnost: E; Object Layer Attributes #1, Systém kotvení: -; Object Layer Attributes #1, Součinitel prostupu tepla: 0.039; Object Layer Attributes #1, Součinitel difúzního odporu: 20 - 40; Object Layer Attributes #1, Způsob spojení vrstev: Mechanicky kotvený; Object Layer Attributes #2, Kód prvku: TM02.04.0008; Object Layer Attributes #2, U-hodnota: 0; Object Layer Attributes #2, Požární odolnost: A; Object Layer Attributes #2, Třída pevnosti ocele: B500B; Object Layer Attributes #2, Funkce: Ano; Object Layer Attributes #2, Stupeň vyztužení: 120; Object Layer Attributes #2, Podlaží: 2.NP; Object Layer Attributes #2, Třída pevnosti betonu: C25/30-XC1; Object Layer Attributes #2, Krytí výztuže: 25mm; Object Layer Attributes #2, Statická funkce: Ano; Object Layer Attributes #3, Kód prvku: TI06.04.1008; Object Layer Attributes #3, Požární odolnost: A1; Object Layer Attributes #3, Systém kotvení: -; Object Layer Attributes #3, Součinitel prostupu tepla: 0.036; Object Layer Attributes #3, Součinitel difúzního odporu: 1; Object Layer Attributes #3, Způsob spojení vrstev: Lepený + mechanicky kotvený
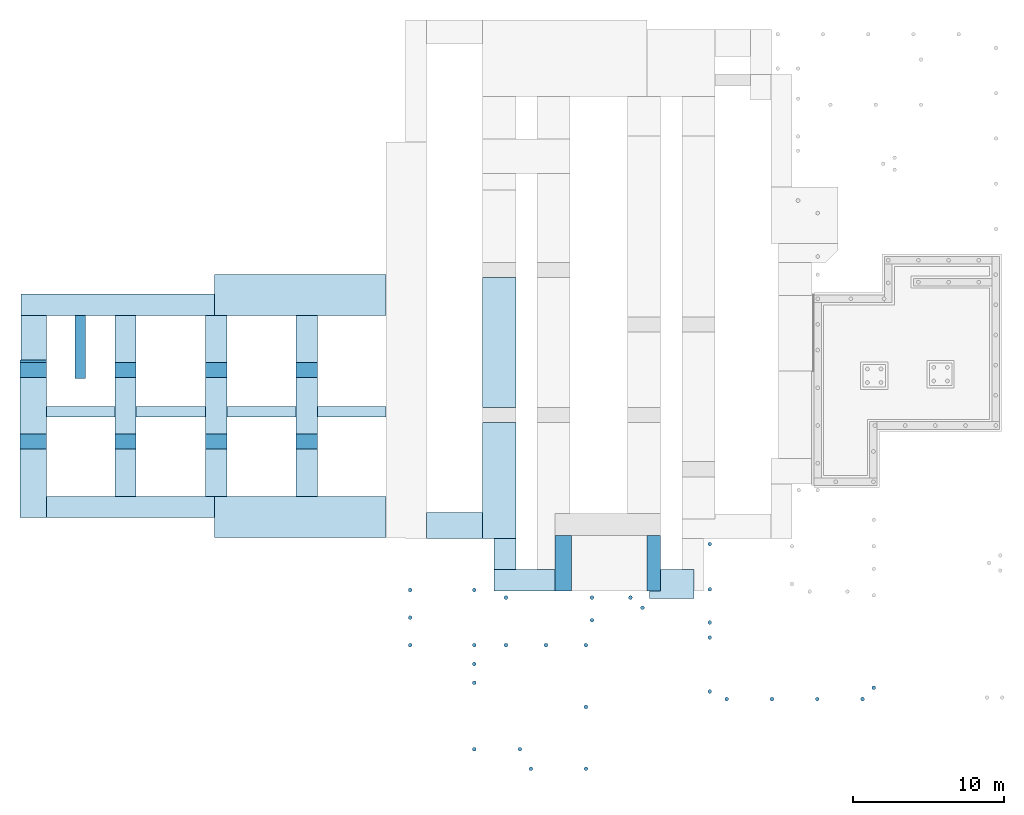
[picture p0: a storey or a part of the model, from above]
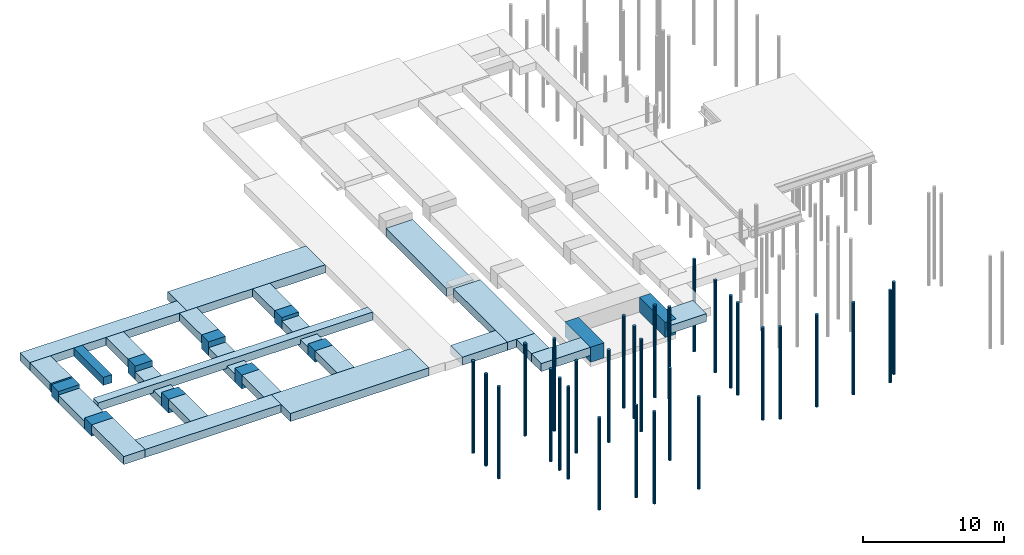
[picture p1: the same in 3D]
Properties of the parts of a building model (IFC4), part 38 of 45

# IfcWall (2385)
Name | In | Material | Faktor | Označení | Požární odolnost | Allright_Stavebni_dil_ID | Jednotka | Název_objektu | Object Layer Attributes #1, Status | Object Layer Attributes #1, Práce | Object Layer Attributes #1, Materiál | Object Layer Attributes #1, Staticky nosná konstrukce | Object Layer Attributes #1, Allright_Stavebni_dil_ID | Object Layer Attributes #1, Jednotka | Object Layer Attributes #1, Název_objektu | ThermalTransmittance (W/K/m2) | Width (m) | GrossSideArea (m2) | NetSideArea (m2) | GrossVolume (m3) | Length (m) | NetVolume (m3) | GrossFootprintArea (m2) | Height (m)
MINERÁLNÍ VATA | Půdorys 2.NP | EPS 0.02 m, ZELEZOBETONOVÁ KCE 0.2 m, MINERÁLNÍ VATA 0.16 m |  | MINERÁLNÍ VATA |  | 1564HWa0000001064 | m3 | Celá stěna | Nový | Zateplovací systémy | EPS | no | 1564Stě0000001065 | m3 | Stěna |  | 0.38 | 12.76 | 12.76 | 3.515 | 9.768 | 3.515 | 3.705 | 1.3 | NEMSOK - Object Layer Attributes #2, 2D interakce: yes; Object Layer Attributes #2, Status: Nový; Object Layer Attributes #2, Práce: Betonářské práce; Object Layer Attributes #2, Materiál: ZELEZOBETONOVÁ KCE; Object Layer Attributes #2, Allright_Stavebni_dil_ID: 1564Stě0000001066; Object Layer Attributes #2, Jednotka: m3; Object Layer Attributes #2, Název_objektu: Stěna; Object Layer Attributes #3, 2D interakce: yes; Object Layer Attributes #3, Status: Nový; Object Layer Attributes #3, Práce: Zateplovací systémy; Object Layer Attributes #3, Materiál: MINERÁLNÍ VATA; Object Layer Attributes #3, Allright_Stavebni_dil_ID: 1564Stě0000001067; Object Layer Attributes #3, Jednotka: m3; Object Layer Attributes #3, Název_objektu: Stěna; Object Layer Attributes #2, Staticky nosná konstrukce: yes; Object Layer Attributes #3, Staticky nosná konstrukce: no; Object Layer Attributes #1, Kód prvku: TI01.04.1005; Object Layer Attributes #1, Požární odolnost: E; Object Layer Attributes #1, Systém kotvení: -; Object Layer Attributes #1, Součinitel prostupu tepla: 0.039; Object Layer Attributes #1, Součinitel difúzního odporu: 20 - 40; Object Layer Attributes #1, Způsob spojení vrstev: Mechanicky kotvený; Object Layer Attributes #2, Kód prvku: TM02.04.0009; Object Layer Attributes #2, U-hodnota: 0; Object Layer Attributes #2, Požární odolnost: A; Object Layer Attributes #2, Třída pevnosti ocele: B500B; Object Layer Attributes #2, Funkce: Ano; Object Layer Attributes #2, Stupeň vyztužení: 120; Object Layer Attributes #2, Podlaží: 2.NP; Object Layer Attributes #2, Třída pevnosti betonu: C25/30-XC1; Object Layer Attributes #2, Krytí výztuže: 25mm; Object Layer Attributes #2, Statická funkce: Ano; Object Layer Attributes #3, Kód prvku: TI06.04.1009; Object Layer Attributes #3, Požární odolnost: A1; Object Layer Attributes #3, Systém kotvení: -; Object Layer Attributes #3, Součinitel prostupu tepla: 0.036; Object Layer Attributes #3, Součinitel difúzního odporu: 1; Object Layer Attributes #3, Způsob spojení vrstev: Lepený + mechanicky kotvený
MINERÁLNÍ VATA | Půdorys 2.NP | EPS 0.02 m, ZELEZOBETONOVÁ KCE 0.2 m, MINERÁLNÍ VATA 0.16 m |  | MINERÁLNÍ VATA |  | 1564HWa0000001082 | m3 | Celá stěna | Nový | Zateplovací systémy | EPS | no | 1564Stě0000001083 | m3 | Stěna |  | 0.38 | 4.849 | 4.849 | 1.289 | 3.623 | 1.289 | 1.359 | 1.3 | NEMSOK - Object Layer Attributes #2, 2D interakce: yes; Object Layer Attributes #2, Status: Nový; Object Layer Attributes #2, Práce: Betonářské práce; Object Layer Attributes #2, Materiál: ZELEZOBETONOVÁ KCE; Object Layer Attributes #2, Allright_Stavebni_dil_ID: 1564Stě0000001084; Object Layer Attributes #2, Jednotka: m3; Object Layer Attributes #2, Název_objektu: Stěna; Object Layer Attributes #3, 2D interakce: yes; Object Layer Attributes #3, Status: Nový; Object Layer Attributes #3, Práce: Zateplovací systémy; Object Layer Attributes #3, Materiál: MINERÁLNÍ VATA; Object Layer Attributes #3, Allright_Stavebni_dil_ID: 1564Stě0000001085; Object Layer Attributes #3, Jednotka: m3; Object Layer Attributes #3, Název_objektu: Stěna; Object Layer Attributes #2, Staticky nosná konstrukce: yes; Object Layer Attributes #3, Staticky nosná konstrukce: no; Object Layer Attributes #1, Kód prvku: TI01.04.1006; Object Layer Attributes #1, Požární odolnost: E; Object Layer Attributes #1, Systém kotvení: -; Object Layer Attributes #1, Součinitel prostupu tepla: 0.039; Object Layer Attributes #1, Součinitel difúzního odporu: 20 - 40; Object Layer Attributes #1, Způsob spojení vrstev: Mechanicky kotvený; Object Layer Attributes #2, Kód prvku: TM02.04.0010; Object Layer Attributes #2, U-hodnota: 0; Object Layer Attributes #2, Požární odolnost: A; Object Layer Attributes #2, Třída pevnosti ocele: B500B; Object Layer Attributes #2, Funkce: Ano; Object Layer Attributes #2, Stupeň vyztužení: 120; Object Layer Attributes #2, Podlaží: 2.NP; Object Layer Attributes #2, Třída pevnosti betonu: C25/30-XC1; Object Layer Attributes #2, Krytí výztuže: 25mm; Object Layer Attributes #2, Statická funkce: Ano; Object Layer Attributes #3, Kód prvku: TI06.04.1010; Object Layer Attributes #3, Požární odolnost: A1; Object Layer Attributes #3, Systém kotvení: -; Object Layer Attributes #3, Součinitel prostupu tepla: 0.036; Object Layer Attributes #3, Součinitel difúzního odporu: 1; Object Layer Attributes #3, Způsob spojení vrstev: Lepený + mechanicky kotvený
MINERÁLNÍ VATA | Půdorys 2.NP | EPS 0.02 m, ZELEZOBETONOVÁ KCE 0.2 m, MINERÁLNÍ VATA 0.16 m |  | MINERÁLNÍ VATA |  | 1564HWa0000001113 | m3 | Celá stěna | Nový | Zateplovací systémy | EPS | no | 1564Stě0000001114 | m3 | Stěna |  | 0.38 | 2.99 | 2.99 | 0.762 | 2.14 | 0.762 | 0.796 | 1.3 | NEMSOK - Object Layer Attributes #2, 2D interakce: yes; Object Layer Attributes #2, Status: Nový; Object Layer Attributes #2, Práce: Betonářské práce; Object Layer Attributes #2, Materiál: ZELEZOBETONOVÁ KCE; Object Layer Attributes #2, Allright_Stavebni_dil_ID: 1564Stě0000001115; Object Layer Attributes #2, Jednotka: m3; Object Layer Attributes #2, Název_objektu: Stěna; Object Layer Attributes #3, 2D interakce: yes; Object Layer Attributes #3, Status: Nový; Object Layer Attributes #3, Práce: Zateplovací systémy; Object Layer Attributes #3, Materiál: MINERÁLNÍ VATA; Object Layer Attributes #3, Allright_Stavebni_dil_ID: 1564Stě0000001116; Object Layer Attributes #3, Jednotka: m3; Object Layer Attributes #3, Název_objektu: Stěna; Object Layer Attributes #2, Staticky nosná konstrukce: yes; Object Layer Attributes #3, Staticky nosná konstrukce: no; Object Layer Attributes #1, Kód prvku: TI01.04.1007; Object Layer Attributes #1, Požární odolnost: E; Object Layer Attributes #1, Systém kotvení: -; Object Layer Attributes #1, Součinitel prostupu tepla: 0.039; Object Layer Attributes #1, Součinitel difúzního odporu: 20 - 40; Object Layer Attributes #1, Způsob spojení vrstev: Mechanicky kotvený; Object Layer Attributes #2, Kód prvku: TM02.04.0011; Object Layer Attributes #2, U-hodnota: 0; Object Layer Attributes #2, Požární odolnost: A; Object Layer Attributes #2, Třída pevnosti ocele: B500B; Object Layer Attributes #2, Funkce: Ano; Object Layer Attributes #2, Stupeň vyztužení: 120; Object Layer Attributes #2, Podlaží: 2.NP; Object Layer Attributes #2, Třída pevnosti betonu: C25/30-XC1; Object Layer Attributes #2, Krytí výztuže: 25mm; Object Layer Attributes #2, Statická funkce: Ano; Object Layer Attributes #3, Kód prvku: TI06.04.1011; Object Layer Attributes #3, Požární odolnost: A1; Object Layer Attributes #3, Systém kotvení: -; Object Layer Attributes #3, Součinitel prostupu tepla: 0.036; Object Layer Attributes #3, Součinitel difúzního odporu: 1; Object Layer Attributes #3, Způsob spojení vrstev: Lepený + mechanicky kotvený
MINERÁLNÍ VATA | Půdorys 2.NP | EPS 0.02 m, ZELEZOBETONOVÁ KCE 0.2 m, MINERÁLNÍ VATA 0.16 m |  | MINERÁLNÍ VATA |  | 1564HWa0000001134 | m3 | Celá stěna | Nový | Zateplovací systémy | EPS | no | 1564Stě0000001135 | m3 | Stěna |  | 0.38 | 13.26 | 13.26 | 3.676 | 10.2 | 3.676 | 3.876 | 1.3 | NEMSOK - Object Layer Attributes #2, 2D interakce: yes; Object Layer Attributes #2, Status: Nový; Object Layer Attributes #2, Práce: Betonářské práce; Object Layer Attributes #2, Materiál: ZELEZOBETONOVÁ KCE; Object Layer Attributes #2, Allright_Stavebni_dil_ID: 1564Stě0000001136; Object Layer Attributes #2, Jednotka: m3; Object Layer Attributes #2, Název_objektu: Stěna; Object Layer Attributes #3, 2D interakce: yes; Object Layer Attributes #3, Status: Nový; Object Layer Attributes #3, Práce: Zateplovací systémy; Object Layer Attributes #3, Materiál: MINERÁLNÍ VATA; Object Layer Attributes #3, Allright_Stavebni_dil_ID: 1564Stě0000001137; Object Layer Attributes #3, Jednotka: m3; Object Layer Attributes #3, Název_objektu: Stěna; Object Layer Attributes #2, Staticky nosná konstrukce: yes; Object Layer Attributes #3, Staticky nosná konstrukce: no; Object Layer Attributes #1, Kód prvku: TI01.04.1008; Object Layer Attributes #1, Požární odolnost: E; Object Layer Attributes #1, Systém kotvení: -; Object Layer Attributes #1, Součinitel prostupu tepla: 0.039; Object Layer Attributes #1, Součinitel difúzního odporu: 20 - 40; Object Layer Attributes #1, Způsob spojení vrstev: Mechanicky kotvený; Object Layer Attributes #2, Kód prvku: TM02.04.0012; Object Layer Attributes #2, U-hodnota: 0; Object Layer Attributes #2, Požární odolnost: A; Object Layer Attributes #2, Třída pevnosti ocele: B500B; Object Layer Attributes #2, Funkce: Ano; Object Layer Attributes #2, Stupeň vyztužení: 120; Object Layer Attributes #2, Podlaží: 2.NP; Object Layer Attributes #2, Třída pevnosti betonu: C25/30-XC1; Object Layer Attributes #2, Krytí výztuže: 25mm; Object Layer Attributes #2, Statická funkce: Ano; Object Layer Attributes #3, Kód prvku: TI06.04.1012; Object Layer Attributes #3, Požární odolnost: A1; Object Layer Attributes #3, Systém kotvení: -; Object Layer Attributes #3, Součinitel prostupu tepla: 0.036; Object Layer Attributes #3, Součinitel difúzního odporu: 1; Object Layer Attributes #3, Způsob spojení vrstev: Lepený + mechanicky kotvený
MINERÁLNÍ VATA | Půdorys 2.NP | EPS 0.02 m, ZELEZOBETONOVÁ KCE 0.2 m, MINERÁLNÍ VATA 0.16 m |  | MINERÁLNÍ VATA |  | 1564HWa0000001165 | m3 | Celá stěna | Nový | Zateplovací systémy | EPS | no | 1564Stě0000001166 | m3 | Stěna |  | 0.38 | 0.65 | 0.65 | 0.087 | 0.313 | 0.087 | 0.089 | 1.3 | NEMSOK - Object Layer Attributes #2, 2D interakce: yes; Object Layer Attributes #2, Status: Nový; Object Layer Attributes #2, Práce: Betonářské práce; Object Layer Attributes #2, Materiál: ZELEZOBETONOVÁ KCE; Object Layer Attributes #2, Allright_Stavebni_dil_ID: 1564Stě0000001167; Object Layer Attributes #2, Jednotka: m3; Object Layer Attributes #2, Název_objektu: Stěna; Object Layer Attributes #3, 2D interakce: yes; Object Layer Attributes #3, Status: Nový; Object Layer Attributes #3, Práce: Zateplovací systémy; Object Layer Attributes #3, Materiál: MINERÁLNÍ VATA; Object Layer Attributes #3, Allright_Stavebni_dil_ID: 1564Stě0000001168; Object Layer Attributes #3, Jednotka: m3; Object Layer Attributes #3, Název_objektu: Stěna; Object Layer Attributes #2, Staticky nosná konstrukce: yes; Object Layer Attributes #3, Staticky nosná konstrukce: no; Object Layer Attributes #1, Kód prvku: TI01.04.1009; Object Layer Attributes #1, Požární odolnost: E; Object Layer Attributes #1, Systém kotvení: -; Object Layer Attributes #1, Součinitel prostupu tepla: 0.039; Object Layer Attributes #1, Součinitel difúzního odporu: 20 - 40; Object Layer Attributes #1, Způsob spojení vrstev: Mechanicky kotvený; Object Layer Attributes #2, Kód prvku: TM02.04.0013; Object Layer Attributes #2, U-hodnota: 0; Object Layer Attributes #2, Požární odolnost: A; Object Layer Attributes #2, Třída pevnosti ocele: B500B; Object Layer Attributes #2, Funkce: Ano; Object Layer Attributes #2, Stupeň vyztužení: 120; Object Layer Attributes #2, Podlaží: 2.NP; Object Layer Attributes #2, Třída pevnosti betonu: C25/30-XC1; Object Layer Attributes #2, Krytí výztuže: 25mm; Object Layer Attributes #2, Statická funkce: Ano; Object Layer Attributes #3, Kód prvku: TI06.04.1013; Object Layer Attributes #3, Požární odolnost: A1; Object Layer Attributes #3, Systém kotvení: -; Object Layer Attributes #3, Součinitel prostupu tepla: 0.036; Object Layer Attributes #3, Součinitel difúzního odporu: 1; Object Layer Attributes #3, Způsob spojení vrstev: Lepený + mechanicky kotvený
YTONG 300 | Půdorys 2.NP | EPS 0.1 m, YTONG 300 0.3 m |  | YTONG 300 | REI 180 | 1564HWa0000002811 | m3 | Celá stěna | Nový | Zateplovací systémy | EPS | no | 1564Stě0000002812 | m3 | Stěna | 0.541 | 0.4 | 0.66 | 0.66 | 0.165 | 0.45 | 0.165 | 0.15 | 1.1 | NEMSOK - Object Layer Attributes #2, 2D interakce: yes; Object Layer Attributes #2, Status: Nový; Object Layer Attributes #2, Práce: Zednické práce; Object Layer Attributes #2, Materiál: YTONG 300; Object Layer Attributes #2, Allright_Stavebni_dil_ID: 1564Stě0000002813; Object Layer Attributes #2, Jednotka: m3; Object Layer Attributes #2, Název_objektu: Stěna; Object Layer Attributes #2, Staticky nosná konstrukce: no; Object Layer Attributes #1, Kód prvku: TI01.04.1010; Object Layer Attributes #1, Požární odolnost: E; Object Layer Attributes #1, Součinitel prostupu tepla: 0.039; Object Layer Attributes #1, Součinitel difúzního odporu: 20 - 40; Object Layer Attributes #1, Způsob spojení vrstev: Mechanicky kotvený; Object Layer Attributes #2, Kód prvku: SN06.04.2004; Object Layer Attributes #2, U-hodnota: 0.362; Object Layer Attributes #2, Požární odolnost: REI 180; Object Layer Attributes #2, Funkce: Ano; Object Layer Attributes #2, Podlaží: 2.NP; Object Layer Attributes #2, Statická funkce: Ne; Object Layer Attributes #2, Neprůzvučnost: 44 dB; Object Layer Attributes #2, Pevnost zdiva: 2,32 N/mm2; Object Layer Attributes #2, Funkce (venkovní): Ano; Pset_WallCommon - AcousticRating: 48 dB
MINERÁLNÍ VATA | Půdorys 2.NP | MINERÁLNÍ VATA 0.16 m |  | MINERÁLNÍ VATA |  | 1564HWa0000002855 | m3 | Celá stěna | Nový | Zateplovací systémy | MINERÁLNÍ VATA | no | 1564Stě0000002856 | m3 | Stěna |  | 0.16 | 0.588 | 0.588 | 0.094 | 0.7 | 0.094 | 0.112 | 0.84 | NEMSOK - Object Layer Attributes #1, Kód prvku: TI06.04.1014; Object Layer Attributes #1, Požární odolnost: A1; Object Layer Attributes #1, Systém kotvení: -; Object Layer Attributes #1, Součinitel prostupu tepla: 0.036; Object Layer Attributes #1, Součinitel difúzního odporu: 1; Object Layer Attributes #1, Způsob spojení vrstev: Lepený + mechanicky kotvený
MINERÁLNÍ VATA | Půdorys 2.NP | MINERÁLNÍ VATA 0.16 m |  | MINERÁLNÍ VATA |  | 1564HWa0000002864 | m3 | Celá stěna | Nový | Zateplovací systémy | MINERÁLNÍ VATA | no | 1564Stě0000002865 | m3 | Stěna |  | 0.16 | 7.51 | 7.51 | 1.202 | 8.94 | 1.202 | 1.43 | 0.84 | NEMSOK - Object Layer Attributes #1, Kód prvku: TI06.04.1015; Object Layer Attributes #1, Požární odolnost: A1; Object Layer Attributes #1, Systém kotvení: -; Object Layer Attributes #1, Součinitel prostupu tepla: 0.036; Object Layer Attributes #1, Součinitel difúzního odporu: 1; Object Layer Attributes #1, Způsob spojení vrstev: Lepený + mechanicky kotvený
MINERÁLNÍ VATA | Půdorys 2.NP | MINERÁLNÍ VATA 0.16 m | 1 | MINERÁLNÍ VATA |  | 1564HWa0000002872 | m3 | Celá stěna | Nový | Zateplovací systémy | MINERÁLNÍ VATA | no | 1564Stě0000002873 | m3 | Stěna |  | 0.16 | 5.62 | 5.62 | 0.899 | 6.69 | 0.899 | 1.07 | 0.84 | NEMSOK - Object Layer Attributes #1, Kód prvku: TI06.04.1016; Object Layer Attributes #1, Požární odolnost: A1; Object Layer Attributes #1, Systém kotvení: -; Object Layer Attributes #1, Součinitel prostupu tepla: 0.036; Object Layer Attributes #1, Součinitel difúzního odporu: 1; Object Layer Attributes #1, Způsob spojení vrstev: Lepený + mechanicky kotvený
MINERÁLNÍ VATA | Půdorys 2.NP | MINERÁLNÍ VATA 0.16 m | 1 | MINERÁLNÍ VATA |  | 1564HWa0000002884 | m3 | Celá stěna | Nový | Zateplovací systémy | MINERÁLNÍ VATA | no | 1564Stě0000002885 | m3 | Stěna |  | 0.16 | 7.426 | 7.426 | 1.188 | 8.84 | 1.188 | 1.414 | 0.84 | NEMSOK - Object Layer Attributes #1, Kód prvku: TI06.04.1017; Object Layer Attributes #1, Požární odolnost: A1; Object Layer Attributes #1, Systém kotvení: -; Object Layer Attributes #1, Součinitel prostupu tepla: 0.036; Object Layer Attributes #1, Součinitel difúzního odporu: 1; Object Layer Attributes #1, Způsob spojení vrstev: Lepený + mechanicky kotvený
MINERÁLNÍ VATA | Půdorys 2.NP | MINERÁLNÍ VATA 0.16 m | 1 | MINERÁLNÍ VATA |  | 1564HWa0000002896 | m3 | Celá stěna | Nový | Zateplovací systémy | MINERÁLNÍ VATA | no | 1564Stě0000002897 | m3 | Stěna |  | 0.16 | 3.15 | 3.15 | 0.504 | 3.75 | 0.504 | 0.6 | 0.84 | NEMSOK - Object Layer Attributes #1, Kód prvku: TI06.04.1018; Object Layer Attributes #1, Požární odolnost: A1; Object Layer Attributes #1, Systém kotvení: -; Object Layer Attributes #1, Součinitel prostupu tepla: 0.036; Object Layer Attributes #1, Součinitel difúzního odporu: 1; Object Layer Attributes #1, Způsob spojení vrstev: Lepený + mechanicky kotvený
MINERÁLNÍ VATA | Půdorys 2.NP | MINERÁLNÍ VATA 0.16 m | 1 | MINERÁLNÍ VATA |  | 1564HWa0000002908 | m3 | Celá stěna | Nový | Zateplovací systémy | MINERÁLNÍ VATA | no | 1564Stě0000002909 | m3 | Stěna |  | 0.16 | 1.932 | 1.932 | 0.309 | 2.3 | 0.309 | 0.368 | 0.84 | NEMSOK - Object Layer Attributes #1, Kód prvku: TI06.04.1019; Object Layer Attributes #1, Požární odolnost: A1; Object Layer Attributes #1, Systém kotvení: -; Object Layer Attributes #1, Součinitel prostupu tepla: 0.036; Object Layer Attributes #1, Součinitel difúzního odporu: 1; Object Layer Attributes #1, Způsob spojení vrstev: Lepený + mechanicky kotvený
MINERÁLNÍ VATA | Půdorys 2.NP | MINERÁLNÍ VATA 0.16 m | 1 | MINERÁLNÍ VATA |  | 1564HWa0000002921 | m3 | Celá stěna | Nový | Zateplovací systémy | MINERÁLNÍ VATA | no | 1564Stě0000002922 | m3 | Stěna |  | 0.16 | 1.882 | 1.882 | 0.301 | 2.24 | 0.301 | 0.358 | 0.84 | NEMSOK - Object Layer Attributes #1, Kód prvku: TI06.04.1020; Object Layer Attributes #1, Požární odolnost: A1; Object Layer Attributes #1, Systém kotvení: -; Object Layer Attributes #1, Součinitel prostupu tepla: 0.036; Object Layer Attributes #1, Součinitel difúzního odporu: 1; Object Layer Attributes #1, Způsob spojení vrstev: Lepený + mechanicky kotvený
MINERÁLNÍ VATA | Půdorys 2.NP | MINERÁLNÍ VATA 0.16 m |  | MINERÁLNÍ VATA |  | 1564HWa0000002933 | m3 | Celá stěna | Nový | Zateplovací systémy | MINERÁLNÍ VATA | no | 1564Stě0000002934 | m3 | Stěna |  | 0.16 | 1.848 | 1.848 | 0.296 | 2.2 | 0.296 | 0.352 | 0.84 | NEMSOK - Object Layer Attributes #1, Kód prvku: TI06.04.1021; Object Layer Attributes #1, Požární odolnost: A1; Object Layer Attributes #1, Systém kotvení: -; Object Layer Attributes #1, Součinitel prostupu tepla: 0.036; Object Layer Attributes #1, Součinitel difúzního odporu: 1; Object Layer Attributes #1, Způsob spojení vrstev: Lepený + mechanicky kotvený
EPS | Půdorys 2.NP | EPS 0.1 m |  | EPS |  | 1564HWa0000003374 | m3 | Celá stěna | Nový | Zateplovací systémy | EPS | no | 1564Stě0000003375 | m3 | Stěna |  | 0.1 | 0.99 | 0.99 | 0.099 | 0.6 | 0.099 | 0.06 | 1.65 | NEMSOK - Object Layer Attributes #1, Kód prvku: TI01.04.0011; Object Layer Attributes #1, Požární odolnost: E; Object Layer Attributes #1, Systém kotvení: -; Object Layer Attributes #1, Součinitel prostupu tepla: 0.039; Object Layer Attributes #1, Součinitel difúzního odporu: 20 - 40; Object Layer Attributes #1, Způsob spojení vrstev: Lepený + mechanicky kotvený
EPS | Půdorys 2.NP | EPS 0.1 m |  | EPS |  | 1564HWa0000003381 | m3 | Celá stěna | Nový | Zateplovací systémy | EPS | no | 1564Stě0000003382 | m3 | Stěna |  | 0.1 | 0.36 | 0.36 | 0.036 | 0.6 | 0.036 | 0.06 | 0.6 | NEMSOK - Object Layer Attributes #1, Kód prvku: TI01.04.0012; Object Layer Attributes #1, Požární odolnost: E; Object Layer Attributes #1, Systém kotvení: -; Object Layer Attributes #1, Součinitel prostupu tepla: 0.039; Object Layer Attributes #1, Součinitel difúzního odporu: 20 - 40; Object Layer Attributes #1, Způsob spojení vrstev: Lepený + mechanicky kotvený
EPS | Půdorys 2.NP | EPS 0.1 m |  | EPS |  | 1564HWa0000003388 | m3 | Celá stěna | Nový | Zateplovací systémy | EPS | no | 1564Stě0000003389 | m3 | Stěna |  | 0.1 | 1.98 | 1.98 | 0.198 | 3.3 | 0.198 | 0.33 | 0.6 | NEMSOK - Object Layer Attributes #1, Kód prvku: TI01.04.0013; Object Layer Attributes #1, Požární odolnost: E; Object Layer Attributes #1, Systém kotvení: -; Object Layer Attributes #1, Součinitel prostupu tepla: 0.039; Object Layer Attributes #1, Součinitel difúzního odporu: 20 - 40; Object Layer Attributes #1, Způsob spojení vrstev: Lepený + mechanicky kotvený
EPS | Půdorys 2.NP | EPS 0.1 m |  | EPS |  | 1564HWa0000003399 | m3 | Celá stěna | Nový | Zateplovací systémy | EPS | no | 1564Stě0000003400 | m3 | Stěna |  | 0.1 | 2.088 | 2.088 | 0.209 | 3.48 | 0.209 | 0.348 | 0.6 | NEMSOK - Object Layer Attributes #1, Kód prvku: TI01.04.0014; Object Layer Attributes #1, Požární odolnost: E; Object Layer Attributes #1, Systém kotvení: -; Object Layer Attributes #1, Součinitel prostupu tepla: 0.039; Object Layer Attributes #1, Součinitel difúzního odporu: 20 - 40; Object Layer Attributes #1, Způsob spojení vrstev: Lepený + mechanicky kotvený
EPS | Půdorys 2.NP | EPS 0.1 m |  | EPS |  | 1564HWa0798450721 | m3 | Celá stěna | Nový | Zateplovací systémy | EPS | no | 1564Stě0798450725 | m3 | Stěna |  | 0.1 | 1.68 | 0.93 | 0.168 | 2.8 | 0.093 | 0.28 | 0.6 | NEMSOK - Object Layer Attributes #1, Kód prvku: TI01.04.0015; Object Layer Attributes #1, Požární odolnost: E; Object Layer Attributes #1, Systém kotvení: -; Object Layer Attributes #1, Součinitel prostupu tepla: 0.039; Object Layer Attributes #1, Součinitel difúzního odporu: 20 - 40; Object Layer Attributes #1, Způsob spojení vrstev: Lepený + mechanicky kotvený
EPS | Půdorys 2.NP | EPS 0.15 m |  | EPS |  | 1564HWa0798450797 | m3 | Celá stěna | Nový | Zateplovací systémy | EPS | no | 1564Stě0798450798 | m3 | Stěna |  | 0.15 | 4.8 | 4.8 | 0.72 | 8 | 0.72 | 1.2 | 0.6 | NEMSOK - Object Layer Attributes #1, Kód prvku: TI01.04.0016; Object Layer Attributes #1, Požární odolnost: E; Object Layer Attributes #1, Systém kotvení: -; Object Layer Attributes #1, Součinitel prostupu tepla: 0.039; Object Layer Attributes #1, Součinitel difúzního odporu: 20 - 40; Object Layer Attributes #1, Způsob spojení vrstev: Lepený + mechanicky kotvený
MINERÁLNÍ VATA | Půdorys 2.NP | MINERÁLNÍ VATA 0.3 m, ZELEZOBETONOVÁ KCE 0.25 m, MINERÁLNÍ VATA 0.16 m |  | MINERÁLNÍ VATA |  | 1564HWa0798450867 | m3 | Celá stěna | Nový | Zateplovací systémy | MINERÁLNÍ VATA | no | 1564Stě0798450868 | m3 | Stěna |  | 0.71 | 30.82 | 30.82 | 17.234 | 26.517 | 17.234 | 18.865 | 1.15 | NEMSOK - Object Layer Attributes #2, 2D interakce: yes; Object Layer Attributes #2, Status: Nový; Object Layer Attributes #2, Práce: Betonářské práce; Object Layer Attributes #2, Materiál: ZELEZOBETONOVÁ KCE; Object Layer Attributes #2, Allright_Stavebni_dil_ID: 1564Stě0798450869; Object Layer Attributes #2, Jednotka: m3; Object Layer Attributes #2, Název_objektu: Stěna; Object Layer Attributes #3, 2D interakce: yes; Object Layer Attributes #3, Status: Nový; Object Layer Attributes #3, Práce: Zateplovací systémy; Object Layer Attributes #3, Materiál: MINERÁLNÍ VATA; Object Layer Attributes #3, Allright_Stavebni_dil_ID: 1564Stě0798450870; Object Layer Attributes #3, Jednotka: m3; Object Layer Attributes #3, Název_objektu: Stěna; Object Layer Attributes #2, Staticky nosná konstrukce: yes; Object Layer Attributes #3, Staticky nosná konstrukce: no; Object Layer Attributes #1, Kód prvku: TI06.04.0006; Object Layer Attributes #1, Požární odolnost: A1; Object Layer Attributes #1, Systém kotvení: -; Object Layer Attributes #1, Součinitel prostupu tepla: 0.036; Object Layer Attributes #1, Součinitel difúzního odporu: 1; Object Layer Attributes #1, Způsob spojení vrstev: Lepený + mechanicky kotvený; Object Layer Attributes #2, Kód prvku: TM02.04.0016; Object Layer Attributes #2, U-hodnota: 0; Object Layer Attributes #2, Požární odolnost: A; Object Layer Attributes #2, Třída pevnosti ocele: B500B; Object Layer Attributes #2, Funkce: Ano; Object Layer Attributes #2, Stupeň vyztužení: 180; Object Layer Attributes #2, Podlaží: 2.NP; Object Layer Attributes #2, Třída pevnosti betonu: C25/30-XC1; Object Layer Attributes #2, Krytí výztuže: 25mm; Object Layer Attributes #2, Statická funkce: Ano; Object Layer Attributes #3, Kód prvku: TI06.04.1023; Object Layer Attributes #3, Požární odolnost: A1; Object Layer Attributes #3, Systém kotvení: -; Object Layer Attributes #3, Součinitel prostupu tepla: 0.036; Object Layer Attributes #3, Součinitel difúzního odporu: 1; Object Layer Attributes #3, Způsob spojení vrstev: Lepený + mechanicky kotvený
MINERÁLNÍ VATA | Půdorys 2.NP | MINERÁLNÍ VATA 0.3 m, ZELEZOBETONOVÁ KCE 0.25 m, MINERÁLNÍ VATA 0.16 m |  | MINERÁLNÍ VATA |  | 1564HWa0798450897 | m3 | Celá stěna | Nový | Zateplovací systémy | MINERÁLNÍ VATA | no | 1564Stě0798450898 | m3 | Stěna |  | 0.71 | 17.043 | 17.043 | 9.41 | 14.38 | 9.41 | 10.266 | 1.15 | NEMSOK - Object Layer Attributes #2, 2D interakce: yes; Object Layer Attributes #2, Status: Nový; Object Layer Attributes #2, Práce: Betonářské práce; Object Layer Attributes #2, Materiál: ZELEZOBETONOVÁ KCE; Object Layer Attributes #2, Allright_Stavebni_dil_ID: 1564Stě0798450899; Object Layer Attributes #2, Jednotka: m3; Object Layer Attributes #2, Název_objektu: Stěna; Object Layer Attributes #3, 2D interakce: yes; Object Layer Attributes #3, Status: Nový; Object Layer Attributes #3, Práce: Zateplovací systémy; Object Layer Attributes #3, Materiál: MINERÁLNÍ VATA; Object Layer Attributes #3, Allright_Stavebni_dil_ID: 1564Stě0798450900; Object Layer Attributes #3, Jednotka: m3; Object Layer Attributes #3, Název_objektu: Stěna; Object Layer Attributes #2, Staticky nosná konstrukce: yes; Object Layer Attributes #3, Staticky nosná konstrukce: no; Object Layer Attributes #1, Kód prvku: TI06.04.0007; Object Layer Attributes #1, Požární odolnost: A1; Object Layer Attributes #1, Systém kotvení: -; Object Layer Attributes #1, Součinitel prostupu tepla: 0.036; Object Layer Attributes #1, Součinitel difúzního odporu: 1; Object Layer Attributes #1, Způsob spojení vrstev: Lepený + mechanicky kotvený; Object Layer Attributes #2, Kód prvku: TM02.04.0017; Object Layer Attributes #2, U-hodnota: 0; Object Layer Attributes #2, Požární odolnost: A; Object Layer Attributes #2, Třída pevnosti ocele: B500B; Object Layer Attributes #2, Funkce: Ano; Object Layer Attributes #2, Stupeň vyztužení: 180; Object Layer Attributes #2, Podlaží: 2.NP; Object Layer Attributes #2, Třída pevnosti betonu: C25/30-XC1; Object Layer Attributes #2, Krytí výztuže: 25mm; Object Layer Attributes #2, Statická funkce: Ano; Object Layer Attributes #3, Kód prvku: TI06.04.1024; Object Layer Attributes #3, Požární odolnost: A1; Object Layer Attributes #3, Systém kotvení: -; Object Layer Attributes #3, Součinitel prostupu tepla: 0.036; Object Layer Attributes #3, Součinitel difúzního odporu: 1; Object Layer Attributes #3, Způsob spojení vrstev: Lepený + mechanicky kotvený
MINERÁLNÍ VATA | Půdorys 2.NP | EPS 0.13 m, ZELEZOBETONOVÁ KCE 0.25 m, MINERÁLNÍ VATA 0.16 m |  | MINERÁLNÍ VATA |  | 1564HWa0798451454 | m3 | Celá stěna | Nový | Zateplovací systémy | EPS | no | 1564Stě0798451455 | m3 | Stěna |  | 0.54 | 8.151 | 8.151 | 3.247 | 8.41 | 3.247 | 4.54 | 0.95 | NEMSOK - Object Layer Attributes #2, 2D interakce: yes; Object Layer Attributes #2, Status: Nový; Object Layer Attributes #2, Práce: Betonářské práce; Object Layer Attributes #2, Materiál: ZELEZOBETONOVÁ KCE; Object Layer Attributes #2, Allright_Stavebni_dil_ID: 1564Stě0798451456; Object Layer Attributes #2, Jednotka: m3; Object Layer Attributes #2, Název_objektu: Stěna; Object Layer Attributes #3, 2D interakce: yes; Object Layer Attributes #3, Status: Nový; Object Layer Attributes #3, Práce: Zateplovací systémy; Object Layer Attributes #3, Materiál: MINERÁLNÍ VATA; Object Layer Attributes #3, Allright_Stavebni_dil_ID: 1564Stě0798451457; Object Layer Attributes #3, Jednotka: m3; Object Layer Attributes #3, Název_objektu: Stěna; Object Layer Attributes #2, Staticky nosná konstrukce: yes; Object Layer Attributes #3, Staticky nosná konstrukce: no; Object Layer Attributes #1, Kód prvku: TI01.04.1017; Object Layer Attributes #1, Požární odolnost: E; Object Layer Attributes #1, Systém kotvení: -; Object Layer Attributes #1, Součinitel prostupu tepla: 0.039; Object Layer Attributes #1, Součinitel difúzního odporu: 20 - 40; Object Layer Attributes #1, Způsob spojení vrstev: Mechanicky kotvený; Object Layer Attributes #2, Kód prvku: TM02.04.0018; Object Layer Attributes #2, U-hodnota: 0; Object Layer Attributes #2, Požární odolnost: A; Object Layer Attributes #2, Třída pevnosti ocele: B500B; Object Layer Attributes #2, Funkce: Ano; Object Layer Attributes #2, Stupeň vyztužení: 180; Object Layer Attributes #2, Podlaží: 2.NP; Object Layer Attributes #2, Třída pevnosti betonu: C25/30-XC1; Object Layer Attributes #2, Krytí výztuže: 25mm; Object Layer Attributes #2, Statická funkce: Ano; Object Layer Attributes #3, Kód prvku: TI06.04.1025; Object Layer Attributes #3, Požární odolnost: A1; Object Layer Attributes #3, Systém kotvení: -; Object Layer Attributes #3, Součinitel prostupu tepla: 0.036; Object Layer Attributes #3, Součinitel difúzního odporu: 1; Object Layer Attributes #3, Způsob spojení vrstev: Lepený + mechanicky kotvený
MINERÁLNÍ VATA | Půdorys 2.NP | EPS 0.13 m, ZELEZOBETONOVÁ KCE 0.25 m, MINERÁLNÍ VATA 0.16 m | 1 | MINERÁLNÍ VATA |  | 1564HWa0798451465 | m3 | Celá stěna | Nový | Zateplovací systémy | EPS | no | 1564Stě0798451466 | m3 | Stěna |  | 0.54 | 1.159 | 1.159 | 0.433 | 1.137 | 0.433 | 0.604 | 0.95 | NEMSOK - Object Layer Attributes #2, 2D interakce: yes; Object Layer Attributes #2, Status: Nový; Object Layer Attributes #2, Práce: Betonářské práce; Object Layer Attributes #2, Materiál: ZELEZOBETONOVÁ KCE; Object Layer Attributes #2, Allright_Stavebni_dil_ID: 1564Stě0798451467; Object Layer Attributes #2, Jednotka: m3; Object Layer Attributes #2, Název_objektu: Stěna; Object Layer Attributes #3, 2D interakce: yes; Object Layer Attributes #3, Status: Nový; Object Layer Attributes #3, Práce: Zateplovací systémy; Object Layer Attributes #3, Materiál: MINERÁLNÍ VATA; Object Layer Attributes #3, Allright_Stavebni_dil_ID: 1564Stě0798451468; Object Layer Attributes #3, Jednotka: m3; Object Layer Attributes #3, Název_objektu: Stěna; Object Layer Attributes #2, Staticky nosná konstrukce: yes; Object Layer Attributes #3, Staticky nosná konstrukce: no; Object Layer Attributes #1, Kód prvku: TI01.04.1018; Object Layer Attributes #1, Požární odolnost: E; Object Layer Attributes #1, Systém kotvení: -; Object Layer Attributes #1, Součinitel prostupu tepla: 0.039; Object Layer Attributes #1, Součinitel difúzního odporu: 20 - 40; Object Layer Attributes #1, Způsob spojení vrstev: Mechanicky kotvený; Object Layer Attributes #2, Kód prvku: TM02.04.0019; Object Layer Attributes #2, U-hodnota: 0; Object Layer Attributes #2, Požární odolnost: A; Object Layer Attributes #2, Třída pevnosti ocele: B500B; Object Layer Attributes #2, Funkce: Ano; Object Layer Attributes #2, Stupeň vyztužení: 180; Object Layer Attributes #2, Podlaží: 2.NP; Object Layer Attributes #2, Třída pevnosti betonu: C25/30-XC1; Object Layer Attributes #2, Krytí výztuže: 25mm; Object Layer Attributes #2, Statická funkce: Ano; Object Layer Attributes #3, Kód prvku: TI06.04.1026; Object Layer Attributes #3, Požární odolnost: A1; Object Layer Attributes #3, Systém kotvení: -; Object Layer Attributes #3, Součinitel prostupu tepla: 0.036; Object Layer Attributes #3, Součinitel difúzního odporu: 1; Object Layer Attributes #3, Způsob spojení vrstev: Lepený + mechanicky kotvený
MINERÁLNÍ VATA | Půdorys 2.NP | EPS 0.08 m, ZELEZOBETONOVÁ KCE 0.25 m, MINERÁLNÍ VATA 0.16 m |  | MINERÁLNÍ VATA |  | 1564HWa0798451493 | m3 | Celá stěna | Nový | Zateplovací systémy | EPS | no | 1564Stě0798451494 | m3 | Stěna |  | 0.49 | 1.092 | 1.093 | 0.467 | 1.37 | 0.467 | 0.692 | 0.95 | NEMSOK - Object Layer Attributes #2, 2D interakce: yes; Object Layer Attributes #2, Status: Nový; Object Layer Attributes #2, Práce: Betonářské práce; Object Layer Attributes #2, Materiál: ZELEZOBETONOVÁ KCE; Object Layer Attributes #2, Allright_Stavebni_dil_ID: 1564Stě0798451495; Object Layer Attributes #2, Jednotka: m3; Object Layer Attributes #2, Název_objektu: Stěna; Object Layer Attributes #3, 2D interakce: yes; Object Layer Attributes #3, Status: Nový; Object Layer Attributes #3, Práce: Zateplovací systémy; Object Layer Attributes #3, Materiál: MINERÁLNÍ VATA; Object Layer Attributes #3, Allright_Stavebni_dil_ID: 1564Stě0798451496; Object Layer Attributes #3, Jednotka: m3; Object Layer Attributes #3, Název_objektu: Stěna; Object Layer Attributes #2, Staticky nosná konstrukce: yes; Object Layer Attributes #3, Staticky nosná konstrukce: no; Object Layer Attributes #1, Kód prvku: TI01.04.1019; Object Layer Attributes #1, Požární odolnost: E; Object Layer Attributes #1, Systém kotvení: -; Object Layer Attributes #1, Součinitel prostupu tepla: 0.039; Object Layer Attributes #1, Součinitel difúzního odporu: 20 - 40; Object Layer Attributes #1, Způsob spojení vrstev: Mechanicky kotvený; Object Layer Attributes #2, Kód prvku: TM02.04.0020; Object Layer Attributes #2, U-hodnota: 0; Object Layer Attributes #2, Požární odolnost: A; Object Layer Attributes #2, Třída pevnosti ocele: B500B; Object Layer Attributes #2, Funkce: Ano; Object Layer Attributes #2, Stupeň vyztužení: 180; Object Layer Attributes #2, Podlaží: 2.NP; Object Layer Attributes #2, Třída pevnosti betonu: C25/30-XC1; Object Layer Attributes #2, Krytí výztuže: 25mm; Object Layer Attributes #2, Statická funkce: Ano; Object Layer Attributes #3, Kód prvku: TI06.04.1027; Object Layer Attributes #3, Požární odolnost: A1; Object Layer Attributes #3, Systém kotvení: -; Object Layer Attributes #3, Součinitel prostupu tepla: 0.036; Object Layer Attributes #3, Součinitel difúzního odporu: 1; Object Layer Attributes #3, Způsob spojení vrstev: Lepený + mechanicky kotvený
MINERÁLNÍ VATA | Půdorys 2.NP | EPS 0.13 m, ZELEZOBETONOVÁ KCE 0.25 m, MINERÁLNÍ VATA 0.16 m |  | MINERÁLNÍ VATA |  | 1564HWa0798451522 | m3 | Celá stěna | Nový | Zateplovací systémy | EPS | no | 1564Stě0798451523 | m3 | Stěna |  | 0.54 | 1.216 | 1.216 | 0.456 | 1.197 | 0.456 | 0.636 | 0.95 | NEMSOK - Object Layer Attributes #2, 2D interakce: yes; Object Layer Attributes #2, Status: Nový; Object Layer Attributes #2, Práce: Betonářské práce; Object Layer Attributes #2, Materiál: ZELEZOBETONOVÁ KCE; Object Layer Attributes #2, Allright_Stavebni_dil_ID: 1564Stě0798451524; Object Layer Attributes #2, Jednotka: m3; Object Layer Attributes #2, Název_objektu: Stěna; Object Layer Attributes #3, 2D interakce: yes; Object Layer Attributes #3, Status: Nový; Object Layer Attributes #3, Práce: Zateplovací systémy; Object Layer Attributes #3, Materiál: MINERÁLNÍ VATA; Object Layer Attributes #3, Allright_Stavebni_dil_ID: 1564Stě0798451525; Object Layer Attributes #3, Jednotka: m3; Object Layer Attributes #3, Název_objektu: Stěna; Object Layer Attributes #2, Staticky nosná konstrukce: yes; Object Layer Attributes #3, Staticky nosná konstrukce: no; Object Layer Attributes #1, Kód prvku: TI01.04.1020; Object Layer Attributes #1, Požární odolnost: E; Object Layer Attributes #1, Systém kotvení: -; Object Layer Attributes #1, Součinitel prostupu tepla: 0.039; Object Layer Attributes #1, Součinitel difúzního odporu: 20 - 40; Object Layer Attributes #1, Způsob spojení vrstev: Mechanicky kotvený; Object Layer Attributes #2, Kód prvku: TM02.04.0021; Object Layer Attributes #2, U-hodnota: 0; Object Layer Attributes #2, Požární odolnost: A; Object Layer Attributes #2, Třída pevnosti ocele: B500B; Object Layer Attributes #2, Funkce: Ano; Object Layer Attributes #2, Stupeň vyztužení: 180; Object Layer Attributes #2, Podlaží: 2.NP; Object Layer Attributes #2, Třída pevnosti betonu: C25/30-XC1; Object Layer Attributes #2, Krytí výztuže: 25mm; Object Layer Attributes #2, Statická funkce: Ano; Object Layer Attributes #3, Kód prvku: TI06.04.1028; Object Layer Attributes #3, Požární odolnost: A1; Object Layer Attributes #3, Systém kotvení: -; Object Layer Attributes #3, Součinitel prostupu tepla: 0.036; Object Layer Attributes #3, Součinitel difúzního odporu: 1; Object Layer Attributes #3, Způsob spojení vrstev: Lepený + mechanicky kotvený
MINERÁLNÍ VATA | Půdorys 2.NP | EPS 0.07 m, ZELEZOBETONOVÁ KCE 0.25 m, MINERÁLNÍ VATA 0.16 m |  | MINERÁLNÍ VATA |  | 1564HWa0798451551 | m3 | Celá stěna | Nový | Zateplovací systémy | EPS | no | 1564Stě0798451552 | m3 | Stěna |  | 0.48 | 2.451 | 2.451 | 0.79 | 2.41 | 0.79 | 1.145 | 0.95 | NEMSOK - Object Layer Attributes #2, 2D interakce: yes; Object Layer Attributes #2, Status: Nový; Object Layer Attributes #2, Práce: Betonářské práce; Object Layer Attributes #2, Materiál: ZELEZOBETONOVÁ KCE; Object Layer Attributes #2, Allright_Stavebni_dil_ID: 1564Stě0798451553; Object Layer Attributes #2, Jednotka: m3; Object Layer Attributes #2, Název_objektu: Stěna; Object Layer Attributes #3, 2D interakce: yes; Object Layer Attributes #3, Status: Nový; Object Layer Attributes #3, Práce: Zateplovací systémy; Object Layer Attributes #3, Materiál: MINERÁLNÍ VATA; Object Layer Attributes #3, Allright_Stavebni_dil_ID: 1564Stě0798451554; Object Layer Attributes #3, Jednotka: m3; Object Layer Attributes #3, Název_objektu: Stěna; Object Layer Attributes #2, Staticky nosná konstrukce: yes; Object Layer Attributes #3, Staticky nosná konstrukce: no; Object Layer Attributes #1, Kód prvku: TI01.04.1021; Object Layer Attributes #1, Požární odolnost: E; Object Layer Attributes #1, Systém kotvení: -; Object Layer Attributes #1, Součinitel prostupu tepla: 0.039; Object Layer Attributes #1, Součinitel difúzního odporu: 20 - 40; Object Layer Attributes #1, Způsob spojení vrstev: Mechanicky kotvený; Object Layer Attributes #2, Kód prvku: TM02.04.0022; Object Layer Attributes #2, U-hodnota: 0; Object Layer Attributes #2, Požární odolnost: A; Object Layer Attributes #2, Třída pevnosti ocele: B500B; Object Layer Attributes #2, Funkce: Ano; Object Layer Attributes #2, Stupeň vyztužení: 180; Object Layer Attributes #2, Podlaží: 2.NP; Object Layer Attributes #2, Třída pevnosti betonu: C25/30-XC1; Object Layer Attributes #2, Krytí výztuže: 25mm; Object Layer Attributes #2, Statická funkce: Ano; Object Layer Attributes #3, Kód prvku: TI06.04.1029; Object Layer Attributes #3, Požární odolnost: A1; Object Layer Attributes #3, Systém kotvení: -; Object Layer Attributes #3, Součinitel prostupu tepla: 0.036; Object Layer Attributes #3, Součinitel difúzního odporu: 1; Object Layer Attributes #3, Způsob spojení vrstev: Lepený + mechanicky kotvený
MINERÁLNÍ VATA | Půdorys 2.NP | EPS |  | MINERÁLNÍ VATA |  | 1564HWa0798451585 | m3 | Celá stěna | Nový | Zateplovací systémy | EPS | no | 1564Stě0798451586 | m3 | Stěna |  | 0.43 | 3.255 | 3.255 | 0.866 | 2.777 | 0.841 | 1.144 | 1.05 | NEMSOK - Object Layer Attributes #2, 2D interakce: yes; Object Layer Attributes #2, Status: Nový; Object Layer Attributes #2, Práce: Betonářské práce; Object Layer Attributes #2, Materiál: ZELEZOBETONOVÁ KCE; Object Layer Attributes #2, Allright_Stavebni_dil_ID: 1564Stě0798451587; Object Layer Attributes #2, Jednotka: m3; Object Layer Attributes #2, Název_objektu: Stěna; Object Layer Attributes #3, 2D interakce: yes; Object Layer Attributes #3, Status: Nový; Object Layer Attributes #3, Práce: Zateplovací systémy; Object Layer Attributes #3, Materiál: MINERÁLNÍ VATA; Object Layer Attributes #3, Allright_Stavebni_dil_ID: 1564Stě0798451588; Object Layer Attributes #3, Jednotka: m3; Object Layer Attributes #3, Název_objektu: Stěna; Object Layer Attributes #2, Staticky nosná konstrukce: yes; Object Layer Attributes #3, Staticky nosná konstrukce: no; Object Layer Attributes #1, Kód prvku: TI01.04.1022; Object Layer Attributes #1, Požární odolnost: E; Object Layer Attributes #1, Systém kotvení: -; Object Layer Attributes #1, Součinitel prostupu tepla: 0.039; Object Layer Attributes #1, Součinitel difúzního odporu: 20 - 40; Object Layer Attributes #1, Způsob spojení vrstev: Mechanicky kotvený; Object Layer Attributes #2, Kód prvku: TM02.04.0023; Object Layer Attributes #2, U-hodnota: 0; Object Layer Attributes #2, Požární odolnost: A; Object Layer Attributes #2, Třída pevnosti ocele: B500B; Object Layer Attributes #2, Funkce: Ano; Object Layer Attributes #2, Stupeň vyztužení: 180; Object Layer Attributes #2, Podlaží: 2.NP; Object Layer Attributes #2, Třída pevnosti betonu: C25/30-XC1; Object Layer Attributes #2, Krytí výztuže: 25mm; Object Layer Attributes #2, Statická funkce: Ano; Object Layer Attributes #3, Kód prvku: TI06.04.1030; Object Layer Attributes #3, Požární odolnost: A1; Object Layer Attributes #3, Systém kotvení: -; Object Layer Attributes #3, Součinitel prostupu tepla: 0.036; Object Layer Attributes #3, Součinitel difúzního odporu: 1; Object Layer Attributes #3, Způsob spojení vrstev: Lepený + mechanicky kotvený
MINERÁLNÍ VATA | Půdorys 2.NP | EPS 0.13 m, ZELEZOBETONOVÁ KCE 0.25 m, MINERÁLNÍ VATA 0.16 m |  | MINERÁLNÍ VATA |  | 1564HWa0798451614 | m3 | Celá stěna | Nový | Zateplovací systémy | EPS | no | 1564Stě0798451615 | m3 | Stěna |  | 0.54 | 3.738 | 3.738 | 1.654 | 3.78 | 1.629 | 2.051 | 1.05 | NEMSOK - Object Layer Attributes #2, 2D interakce: yes; Object Layer Attributes #2, Status: Nový; Object Layer Attributes #2, Práce: Betonářské práce; Object Layer Attributes #2, Materiál: ZELEZOBETONOVÁ KCE; Object Layer Attributes #2, Allright_Stavebni_dil_ID: 1564Stě0798451616; Object Layer Attributes #2, Jednotka: m3; Object Layer Attributes #2, Název_objektu: Stěna; Object Layer Attributes #3, 2D interakce: yes; Object Layer Attributes #3, Status: Nový; Object Layer Attributes #3, Práce: Zateplovací systémy; Object Layer Attributes #3, Materiál: MINERÁLNÍ VATA; Object Layer Attributes #3, Allright_Stavebni_dil_ID: 1564Stě0798451617; Object Layer Attributes #3, Jednotka: m3; Object Layer Attributes #3, Název_objektu: Stěna; Object Layer Attributes #2, Staticky nosná konstrukce: yes; Object Layer Attributes #3, Staticky nosná konstrukce: no; Object Layer Attributes #1, Kód prvku: TI01.04.1023; Object Layer Attributes #1, Požární odolnost: E; Object Layer Attributes #1, Systém kotvení: -; Object Layer Attributes #1, Součinitel prostupu tepla: 0.039; Object Layer Attributes #1, Součinitel difúzního odporu: 20 - 40; Object Layer Attributes #1, Způsob spojení vrstev: Mechanicky kotvený; Object Layer Attributes #2, Kód prvku: TM02.04.0024; Object Layer Attributes #2, U-hodnota: 0; Object Layer Attributes #2, Požární odolnost: A; Object Layer Attributes #2, Třída pevnosti ocele: B500B; Object Layer Attributes #2, Funkce: Ano; Object Layer Attributes #2, Stupeň vyztužení: 180; Object Layer Attributes #2, Podlaží: 2.NP; Object Layer Attributes #2, Třída pevnosti betonu: C25/30-XC1; Object Layer Attributes #2, Krytí výztuže: 25mm; Object Layer Attributes #2, Statická funkce: Ano; Object Layer Attributes #3, Kód prvku: TI06.04.1031; Object Layer Attributes #3, Požární odolnost: A1; Object Layer Attributes #3, Systém kotvení: -; Object Layer Attributes #3, Součinitel prostupu tepla: 0.036; Object Layer Attributes #3, Součinitel difúzního odporu: 1; Object Layer Attributes #3, Způsob spojení vrstev: Lepený + mechanicky kotvený
MINERÁLNÍ VATA | Půdorys 2.NP | EPS 0.1 m, ZELEZOBETONOVÁ KCE 0.25 m, MINERÁLNÍ VATA 0.16 m |  | MINERÁLNÍ VATA |  | 1564HWa0798451648 | m3 | Celá stěna | Nový | Zateplovací systémy | EPS | no | 1564Stě0798451649 | m3 | Stěna |  | 0.51 | 0.63 | 0.63 | 0.278 | 0.673 | 0.278 | 0.351 | 1.05 | NEMSOK - Object Layer Attributes #2, 2D interakce: yes; Object Layer Attributes #2, Status: Nový; Object Layer Attributes #2, Práce: Betonářské práce; Object Layer Attributes #2, Materiál: ZELEZOBETONOVÁ KCE; Object Layer Attributes #2, Allright_Stavebni_dil_ID: 1564Stě0798451650; Object Layer Attributes #2, Jednotka: m3; Object Layer Attributes #2, Název_objektu: Stěna; Object Layer Attributes #3, 2D interakce: yes; Object Layer Attributes #3, Status: Nový; Object Layer Attributes #3, Práce: Zateplovací systémy; Object Layer Attributes #3, Materiál: MINERÁLNÍ VATA; Object Layer Attributes #3, Allright_Stavebni_dil_ID: 1564Stě0798451651; Object Layer Attributes #3, Jednotka: m3; Object Layer Attributes #3, Název_objektu: Stěna; Object Layer Attributes #2, Staticky nosná konstrukce: yes; Object Layer Attributes #3, Staticky nosná konstrukce: no; Object Layer Attributes #1, Kód prvku: TI01.04.1024; Object Layer Attributes #1, Požární odolnost: E; Object Layer Attributes #1, Systém kotvení: -; Object Layer Attributes #1, Součinitel prostupu tepla: 0.039; Object Layer Attributes #1, Součinitel difúzního odporu: 20 - 40; Object Layer Attributes #1, Způsob spojení vrstev: Mechanicky kotvený; Object Layer Attributes #2, Kód prvku: TM02.04.0025; Object Layer Attributes #2, U-hodnota: 0; Object Layer Attributes #2, Požární odolnost: A; Object Layer Attributes #2, Třída pevnosti ocele: B500B; Object Layer Attributes #2, Funkce: Ano; Object Layer Attributes #2, Stupeň vyztužení: 180; Object Layer Attributes #2, Podlaží: 2.NP; Object Layer Attributes #2, Třída pevnosti betonu: C25/30-XC1; Object Layer Attributes #2, Krytí výztuže: 25mm; Object Layer Attributes #2, Statická funkce: Ano; Object Layer Attributes #3, Kód prvku: TI06.04.1032; Object Layer Attributes #3, Požární odolnost: A1; Object Layer Attributes #3, Systém kotvení: -; Object Layer Attributes #3, Součinitel prostupu tepla: 0.036; Object Layer Attributes #3, Součinitel difúzního odporu: 1; Object Layer Attributes #3, Způsob spojení vrstev: Lepený + mechanicky kotvený
MINERÁLNÍ VATA | Půdorys 2.NP | EPS 0.02 m, ZELEZOBETONOVÁ KCE 0.25 m, MINERÁLNÍ VATA 0.16 m |  | MINERÁLNÍ VATA |  | 1564HWa0798451677 | m3 | Celá stěna | Nový | Zateplovací systémy | EPS | no | 1564Stě0798451678 | m3 | Stěna |  | 0.43 | 2.31 | 2.31 | 0.588 | 1.883 | 0.588 | 0.77 | 1.05 | NEMSOK - Object Layer Attributes #2, 2D interakce: yes; Object Layer Attributes #2, Status: Nový; Object Layer Attributes #2, Práce: Betonářské práce; Object Layer Attributes #2, Materiál: ZELEZOBETONOVÁ KCE; Object Layer Attributes #2, Allright_Stavebni_dil_ID: 1564Stě0798451679; Object Layer Attributes #2, Jednotka: m3; Object Layer Attributes #2, Název_objektu: Stěna; Object Layer Attributes #3, 2D interakce: yes; Object Layer Attributes #3, Status: Nový; Object Layer Attributes #3, Práce: Zateplovací systémy; Object Layer Attributes #3, Materiál: MINERÁLNÍ VATA; Object Layer Attributes #3, Allright_Stavebni_dil_ID: 1564Stě0798451680; Object Layer Attributes #3, Jednotka: m3; Object Layer Attributes #3, Název_objektu: Stěna; Object Layer Attributes #2, Staticky nosná konstrukce: yes; Object Layer Attributes #3, Staticky nosná konstrukce: no; Object Layer Attributes #1, Kód prvku: TI01.04.1025; Object Layer Attributes #1, Požární odolnost: E; Object Layer Attributes #1, Systém kotvení: -; Object Layer Attributes #1, Součinitel prostupu tepla: 0.039; Object Layer Attributes #1, Součinitel difúzního odporu: 20 - 40; Object Layer Attributes #1, Způsob spojení vrstev: Mechanicky kotvený; Object Layer Attributes #2, Kód prvku: TM02.04.0026; Object Layer Attributes #2, U-hodnota: 0; Object Layer Attributes #2, Požární odolnost: A; Object Layer Attributes #2, Třída pevnosti ocele: B500B; Object Layer Attributes #2, Funkce: Ano; Object Layer Attributes #2, Stupeň vyztužení: 180; Object Layer Attributes #2, Podlaží: 2.NP; Object Layer Attributes #2, Třída pevnosti betonu: C25/30-XC1; Object Layer Attributes #2, Krytí výztuže: 25mm; Object Layer Attributes #2, Statická funkce: Ano; Object Layer Attributes #3, Kód prvku: TI06.04.1033; Object Layer Attributes #3, Požární odolnost: A1; Object Layer Attributes #3, Systém kotvení: -; Object Layer Attributes #3, Součinitel prostupu tepla: 0.036; Object Layer Attributes #3, Součinitel difúzního odporu: 1; Object Layer Attributes #3, Způsob spojení vrstev: Lepený + mechanicky kotvený
MINERÁLNÍ VATA | Půdorys 2.NP | EPS 0.13 m, ZELEZOBETONOVÁ KCE 0.25 m, MINERÁLNÍ VATA 0.16 m |  | MINERÁLNÍ VATA |  | 1564HWa0798451742 | m3 | Celá stěna | Nový | Zateplovací systémy | EPS | no | 1564Stě0798451743 | m3 | Stěna |  | 0.54 | 5.198 | 5.198 | 2.165 | 4.918 | 2.165 | 2.66 | 1.05 | NEMSOK - Object Layer Attributes #2, 2D interakce: yes; Object Layer Attributes #2, Status: Nový; Object Layer Attributes #2, Práce: Betonářské práce; Object Layer Attributes #2, Materiál: ZELEZOBETONOVÁ KCE; Object Layer Attributes #2, Allright_Stavebni_dil_ID: 1564Stě0798451744; Object Layer Attributes #2, Jednotka: m3; Object Layer Attributes #2, Název_objektu: Stěna; Object Layer Attributes #3, 2D interakce: yes; Object Layer Attributes #3, Status: Nový; Object Layer Attributes #3, Práce: Zateplovací systémy; Object Layer Attributes #3, Materiál: MINERÁLNÍ VATA; Object Layer Attributes #3, Allright_Stavebni_dil_ID: 1564Stě0798451745; Object Layer Attributes #3, Jednotka: m3; Object Layer Attributes #3, Název_objektu: Stěna; Object Layer Attributes #2, Staticky nosná konstrukce: yes; Object Layer Attributes #3, Staticky nosná konstrukce: no; Object Layer Attributes #1, Kód prvku: TI01.04.1026; Object Layer Attributes #1, Požární odolnost: E; Object Layer Attributes #1, Systém kotvení: -; Object Layer Attributes #1, Součinitel prostupu tepla: 0.039; Object Layer Attributes #1, Součinitel difúzního odporu: 20 - 40; Object Layer Attributes #1, Způsob spojení vrstev: Mechanicky kotvený; Object Layer Attributes #2, Kód prvku: TM02.04.0027; Object Layer Attributes #2, U-hodnota: 0; Object Layer Attributes #2, Požární odolnost: A; Object Layer Attributes #2, Třída pevnosti ocele: B500B; Object Layer Attributes #2, Funkce: Ano; Object Layer Attributes #2, Stupeň vyztužení: 180; Object Layer Attributes #2, Podlaží: 2.NP; Object Layer Attributes #2, Třída pevnosti betonu: C25/30-XC1; Object Layer Attributes #2, Krytí výztuže: 25mm; Object Layer Attributes #2, Statická funkce: Ano; Object Layer Attributes #3, Kód prvku: TI06.04.1034; Object Layer Attributes #3, Požární odolnost: A1; Object Layer Attributes #3, Systém kotvení: -; Object Layer Attributes #3, Součinitel prostupu tepla: 0.036; Object Layer Attributes #3, Součinitel difúzního odporu: 1; Object Layer Attributes #3, Způsob spojení vrstev: Lepený + mechanicky kotvený
MINERÁLNÍ VATA | Půdorys 2.NP | EPS 0.08 m, ZELEZOBETONOVÁ KCE 0.25 m, MINERÁLNÍ VATA 0.16 m | 1 | MINERÁLNÍ VATA |  | 1564HWa0798452068 | m3 | Celá stěna | Nový | Zateplovací systémy | EPS | no | 1564Stě0798452071 | m3 | Stěna |  | 0.49 | 1.093 | 1.093 | 0.467 | 1.37 | 0.467 | 0.692 | 0.95 | NEMSOK - Object Layer Attributes #2, 2D interakce: yes; Object Layer Attributes #2, Status: Nový; Object Layer Attributes #2, Práce: Betonářské práce; Object Layer Attributes #2, Materiál: ZELEZOBETONOVÁ KCE; Object Layer Attributes #2, Allright_Stavebni_dil_ID: 1564Stě0798452072; Object Layer Attributes #2, Jednotka: m3; Object Layer Attributes #2, Název_objektu: Stěna; Object Layer Attributes #3, 2D interakce: yes; Object Layer Attributes #3, Status: Nový; Object Layer Attributes #3, Práce: Zateplovací systémy; Object Layer Attributes #3, Materiál: MINERÁLNÍ VATA; Object Layer Attributes #3, Allright_Stavebni_dil_ID: 1564Stě0798452073; Object Layer Attributes #3, Jednotka: m3; Object Layer Attributes #3, Název_objektu: Stěna; Object Layer Attributes #2, Staticky nosná konstrukce: yes; Object Layer Attributes #3, Staticky nosná konstrukce: no; Object Layer Attributes #1, Kód prvku: TI01.04.1027; Object Layer Attributes #1, Požární odolnost: E; Object Layer Attributes #1, Systém kotvení: -; Object Layer Attributes #1, Součinitel prostupu tepla: 0.039; Object Layer Attributes #1, Součinitel difúzního odporu: 20 - 40; Object Layer Attributes #1, Způsob spojení vrstev: Mechanicky kotvený; Object Layer Attributes #2, Kód prvku: TM02.04.0028; Object Layer Attributes #2, U-hodnota: 0; Object Layer Attributes #2, Požární odolnost: A; Object Layer Attributes #2, Třída pevnosti ocele: B500B; Object Layer Attributes #2, Funkce: Ano; Object Layer Attributes #2, Stupeň vyztužení: 180; Object Layer Attributes #2, Podlaží: 2.NP; Object Layer Attributes #2, Třída pevnosti betonu: C25/30-XC1; Object Layer Attributes #2, Krytí výztuže: 25mm; Object Layer Attributes #2, Statická funkce: Ano; Object Layer Attributes #3, Kód prvku: TI06.04.1035; Object Layer Attributes #3, Požární odolnost: A1; Object Layer Attributes #3, Systém kotvení: -; Object Layer Attributes #3, Součinitel prostupu tepla: 0.036; Object Layer Attributes #3, Součinitel difúzního odporu: 1; Object Layer Attributes #3, Způsob spojení vrstev: Lepený + mechanicky kotvený
MINERÁLNÍ VATA | Půdorys 2.NP | EPS 0.13 m, ZELEZOBETONOVÁ KCE 0.25 m, MINERÁLNÍ VATA 0.16 m |  | MINERÁLNÍ VATA |  | 1564HWa0798452187 | m3 | Celá stěna | Nový | Zateplovací systémy | EPS | no | 1564Stě0798452190 | m3 | Stěna |  | 0.54 | 14.82 | 14.82 | 6.004 | 15.6 | 6.004 | 8.424 | 0.95 | NEMSOK - Object Layer Attributes #2, 2D interakce: yes; Object Layer Attributes #2, Status: Nový; Object Layer Attributes #2, Práce: Betonářské práce; Object Layer Attributes #2, Materiál: ZELEZOBETONOVÁ KCE; Object Layer Attributes #2, Allright_Stavebni_dil_ID: 1564Stě0798452191; Object Layer Attributes #2, Jednotka: m3; Object Layer Attributes #2, Název_objektu: Stěna; Object Layer Attributes #3, 2D interakce: yes; Object Layer Attributes #3, Status: Nový; Object Layer Attributes #3, Práce: Zateplovací systémy; Object Layer Attributes #3, Materiál: MINERÁLNÍ VATA; Object Layer Attributes #3, Allright_Stavebni_dil_ID: 1564Stě0798452192; Object Layer Attributes #3, Jednotka: m3; Object Layer Attributes #3, Název_objektu: Stěna; Object Layer Attributes #2, Staticky nosná konstrukce: yes; Object Layer Attributes #3, Staticky nosná konstrukce: no; Object Layer Attributes #1, Kód prvku: TI01.04.1028; Object Layer Attributes #1, Požární odolnost: E; Object Layer Attributes #1, Systém kotvení: -; Object Layer Attributes #1, Součinitel prostupu tepla: 0.039; Object Layer Attributes #1, Součinitel difúzního odporu: 20 - 40; Object Layer Attributes #1, Způsob spojení vrstev: Mechanicky kotvený; Object Layer Attributes #2, Kód prvku: TM02.04.0029; Object Layer Attributes #2, U-hodnota: 0; Object Layer Attributes #2, Požární odolnost: A; Object Layer Attributes #2, Třída pevnosti ocele: B500B; Object Layer Attributes #2, Funkce: Ano; Object Layer Attributes #2, Stupeň vyztužení: 180; Object Layer Attributes #2, Podlaží: 2.NP; Object Layer Attributes #2, Třída pevnosti betonu: C25/30-XC1; Object Layer Attributes #2, Krytí výztuže: 25mm; Object Layer Attributes #2, Statická funkce: Ano; Object Layer Attributes #3, Kód prvku: TI06.04.1036; Object Layer Attributes #3, Požární odolnost: A1; Object Layer Attributes #3, Systém kotvení: -; Object Layer Attributes #3, Součinitel prostupu tepla: 0.036; Object Layer Attributes #3, Součinitel difúzního odporu: 1; Object Layer Attributes #3, Způsob spojení vrstev: Lepený + mechanicky kotvený
MINERÁLNÍ VATA | Půdorys 2.NP | EPS 0.13 m, ZELEZOBETONOVÁ KCE 0.25 m, MINERÁLNÍ VATA 0.16 m |  | MINERÁLNÍ VATA |  | 1564HWa0798452287 | m3 | Celá stěna | Nový | Zateplovací systémy | EPS | no | 1564Stě0798452288 | m3 | Stěna |  | 0.54 | 3.171 | 3.171 | 1.153 | 2.587 | 1.153 | 1.387 | 1.05 | NEMSOK - Object Layer Attributes #2, 2D interakce: yes; Object Layer Attributes #2, Status: Nový; Object Layer Attributes #2, Práce: Betonářské práce; Object Layer Attributes #2, Materiál: ZELEZOBETONOVÁ KCE; Object Layer Attributes #2, Allright_Stavebni_dil_ID: 1564Stě0798452289; Object Layer Attributes #2, Jednotka: m3; Object Layer Attributes #2, Název_objektu: Stěna; Object Layer Attributes #3, 2D interakce: yes; Object Layer Attributes #3, Status: Nový; Object Layer Attributes #3, Práce: Zateplovací systémy; Object Layer Attributes #3, Materiál: MINERÁLNÍ VATA; Object Layer Attributes #3, Allright_Stavebni_dil_ID: 1564Stě0798452290; Object Layer Attributes #3, Jednotka: m3; Object Layer Attributes #3, Název_objektu: Stěna; Object Layer Attributes #2, Staticky nosná konstrukce: yes; Object Layer Attributes #3, Staticky nosná konstrukce: no; Object Layer Attributes #1, Kód prvku: TI01.04.1029; Object Layer Attributes #1, Požární odolnost: E; Object Layer Attributes #1, Systém kotvení: -; Object Layer Attributes #1, Součinitel prostupu tepla: 0.039; Object Layer Attributes #1, Součinitel difúzního odporu: 20 - 40; Object Layer Attributes #1, Způsob spojení vrstev: Mechanicky kotvený; Object Layer Attributes #2, Kód prvku: TM02.04.0030; Object Layer Attributes #2, U-hodnota: 0; Object Layer Attributes #2, Požární odolnost: A; Object Layer Attributes #2, Třída pevnosti ocele: B500B; Object Layer Attributes #2, Funkce: Ano; Object Layer Attributes #2, Stupeň vyztužení: 180; Object Layer Attributes #2, Podlaží: 2.NP; Object Layer Attributes #2, Třída pevnosti betonu: C25/30-XC1; Object Layer Attributes #2, Krytí výztuže: 25mm; Object Layer Attributes #2, Statická funkce: Ano; Object Layer Attributes #3, Kód prvku: TI06.04.1037; Object Layer Attributes #3, Požární odolnost: A1; Object Layer Attributes #3, Systém kotvení: -; Object Layer Attributes #3, Součinitel prostupu tepla: 0.036; Object Layer Attributes #3, Součinitel difúzního odporu: 1; Object Layer Attributes #3, Způsob spojení vrstev: Lepený + mechanicky kotvený
MINERÁLNÍ VATA | Půdorys 2.NP | EPS 0.1 m, ZELEZOBETONOVÁ KCE 0.25 m, MINERÁLNÍ VATA 0.16 m | 1 | MINERÁLNÍ VATA |  | 1564HWa0798452298 | m3 | Celá stěna | Nový | Zateplovací systémy | EPS | no | 1564Stě0798452299 | m3 | Stěna |  | 0.51 | 1.206 | 1.207 | 0.416 | 1.187 | 0.416 | 0.592 | 0.95 | NEMSOK - Object Layer Attributes #2, 2D interakce: yes; Object Layer Attributes #2, Status: Nový; Object Layer Attributes #2, Práce: Betonářské práce; Object Layer Attributes #2, Materiál: ZELEZOBETONOVÁ KCE; Object Layer Attributes #2, Allright_Stavebni_dil_ID: 1564Stě0798452300; Object Layer Attributes #2, Jednotka: m3; Object Layer Attributes #2, Název_objektu: Stěna; Object Layer Attributes #3, 2D interakce: yes; Object Layer Attributes #3, Status: Nový; Object Layer Attributes #3, Práce: Zateplovací systémy; Object Layer Attributes #3, Materiál: MINERÁLNÍ VATA; Object Layer Attributes #3, Allright_Stavebni_dil_ID: 1564Stě0798452301; Object Layer Attributes #3, Jednotka: m3; Object Layer Attributes #3, Název_objektu: Stěna; Object Layer Attributes #2, Staticky nosná konstrukce: yes; Object Layer Attributes #3, Staticky nosná konstrukce: no; Object Layer Attributes #1, Kód prvku: TI01.04.1030; Object Layer Attributes #1, Požární odolnost: E; Object Layer Attributes #1, Systém kotvení: -; Object Layer Attributes #1, Součinitel prostupu tepla: 0.039; Object Layer Attributes #1, Součinitel difúzního odporu: 20 - 40; Object Layer Attributes #1, Způsob spojení vrstev: Mechanicky kotvený; Object Layer Attributes #2, Kód prvku: TM02.04.0031; Object Layer Attributes #2, U-hodnota: 0; Object Layer Attributes #2, Požární odolnost: A; Object Layer Attributes #2, Třída pevnosti ocele: B500B; Object Layer Attributes #2, Funkce: Ano; Object Layer Attributes #2, Stupeň vyztužení: 180; Object Layer Attributes #2, Podlaží: 2.NP; Object Layer Attributes #2, Třída pevnosti betonu: C25/30-XC1; Object Layer Attributes #2, Krytí výztuže: 25mm; Object Layer Attributes #2, Statická funkce: Ano; Object Layer Attributes #3, Kód prvku: TI06.04.1038; Object Layer Attributes #3, Požární odolnost: A1; Object Layer Attributes #3, Systém kotvení: -; Object Layer Attributes #3, Součinitel prostupu tepla: 0.036; Object Layer Attributes #3, Součinitel difúzního odporu: 1; Object Layer Attributes #3, Způsob spojení vrstev: Lepený + mechanicky kotvený
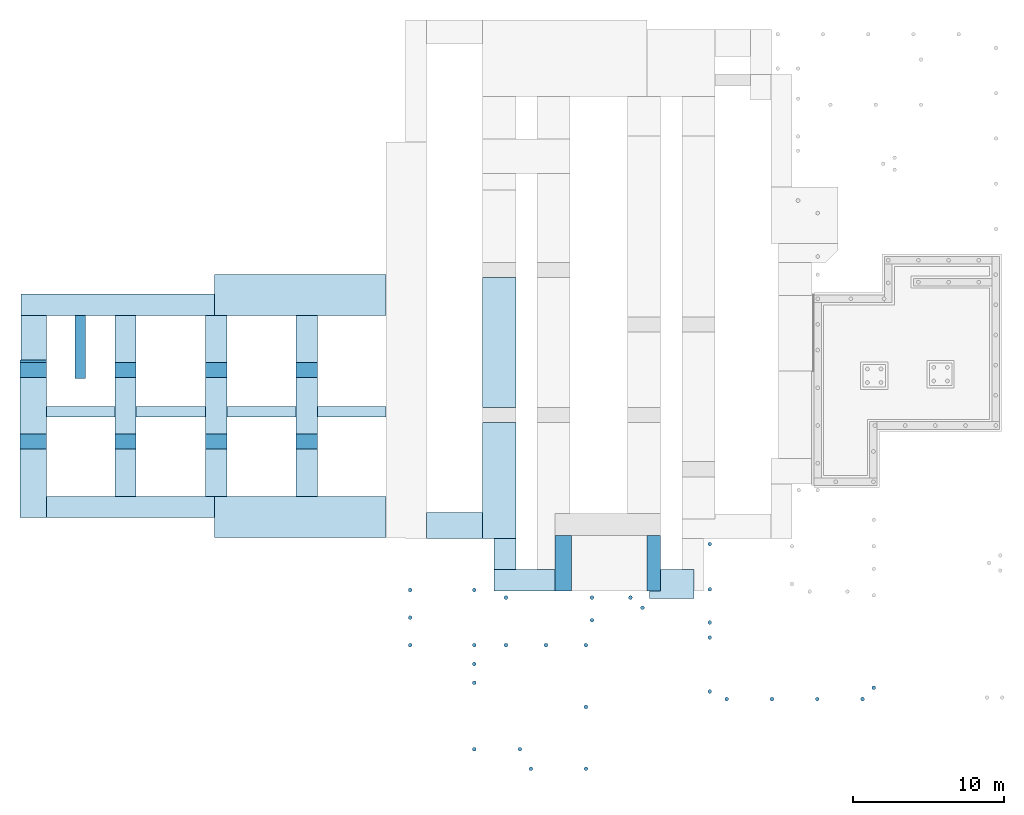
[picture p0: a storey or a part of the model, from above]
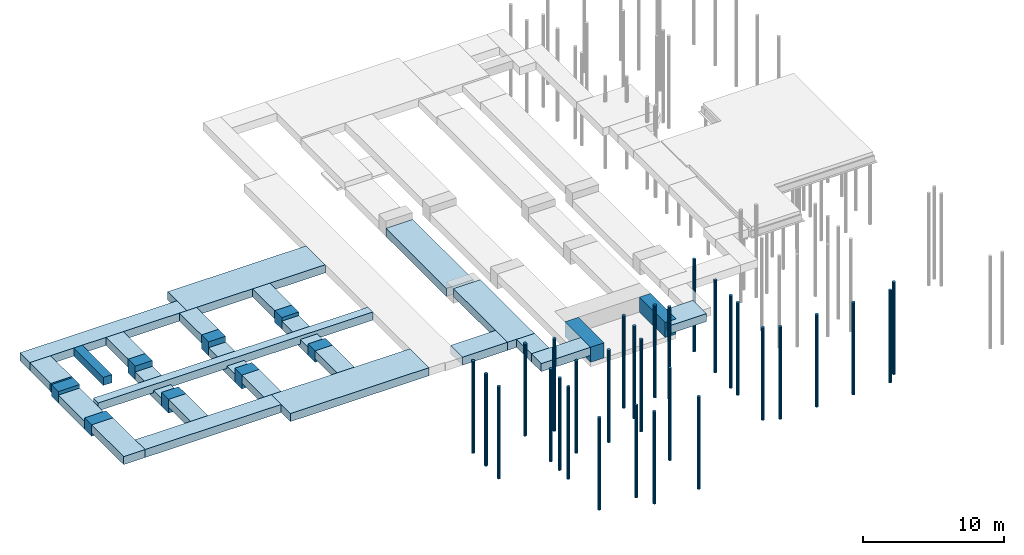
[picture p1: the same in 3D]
Properties of the parts of a building model (IFC4), part 39 of 45

# IfcWall (2385)
Name | In | Material | Faktor | Označení | Požární odolnost | Allright_Stavebni_dil_ID | Jednotka | Název_objektu | Object Layer Attributes #1, Status | Object Layer Attributes #1, Práce | Object Layer Attributes #1, Materiál | Object Layer Attributes #1, Staticky nosná konstrukce | Object Layer Attributes #1, Allright_Stavebni_dil_ID | Object Layer Attributes #1, Jednotka | Object Layer Attributes #1, Název_objektu | ThermalTransmittance (W/K/m2) | Width (m) | GrossSideArea (m2) | NetSideArea (m2) | GrossVolume (m3) | Length (m) | NetVolume (m3) | GrossFootprintArea (m2) | Height (m)
MINERÁLNÍ VATA | Půdorys 2.NP | EPS 0.08 m, ZELEZOBETONOVÁ KCE 0.25 m, MINERÁLNÍ VATA 0.16 m |  | MINERÁLNÍ VATA |  | 1564HWa0798452326 | m3 | Celá stěna | Nový | Zateplovací systémy | EPS | no | 1564Stě0798452327 | m3 | Stěna |  | 0.49 | 1.074 | 1.074 | 0.46 | 1.35 | 0.46 | 0.682 | 0.95 | NEMSOK - Object Layer Attributes #2, 2D interakce: yes; Object Layer Attributes #2, Status: Nový; Object Layer Attributes #2, Práce: Betonářské práce; Object Layer Attributes #2, Materiál: ZELEZOBETONOVÁ KCE; Object Layer Attributes #2, Allright_Stavebni_dil_ID: 1564Stě0798452328; Object Layer Attributes #2, Jednotka: m3; Object Layer Attributes #2, Název_objektu: Stěna; Object Layer Attributes #3, 2D interakce: yes; Object Layer Attributes #3, Status: Nový; Object Layer Attributes #3, Práce: Zateplovací systémy; Object Layer Attributes #3, Materiál: MINERÁLNÍ VATA; Object Layer Attributes #3, Allright_Stavebni_dil_ID: 1564Stě0798452329; Object Layer Attributes #3, Jednotka: m3; Object Layer Attributes #3, Název_objektu: Stěna; Object Layer Attributes #2, Staticky nosná konstrukce: yes; Object Layer Attributes #3, Staticky nosná konstrukce: no; Object Layer Attributes #1, Kód prvku: TI01.04.1031; Object Layer Attributes #1, Požární odolnost: E; Object Layer Attributes #1, Systém kotvení: -; Object Layer Attributes #1, Součinitel prostupu tepla: 0.039; Object Layer Attributes #1, Součinitel difúzního odporu: 20 - 40; Object Layer Attributes #1, Způsob spojení vrstev: Mechanicky kotvený; Object Layer Attributes #2, Kód prvku: TM02.04.0032; Object Layer Attributes #2, U-hodnota: 0; Object Layer Attributes #2, Požární odolnost: A; Object Layer Attributes #2, Třída pevnosti ocele: B500B; Object Layer Attributes #2, Funkce: Ano; Object Layer Attributes #2, Stupeň vyztužení: 180; Object Layer Attributes #2, Podlaží: 2.NP; Object Layer Attributes #2, Třída pevnosti betonu: C25/30-XC1; Object Layer Attributes #2, Krytí výztuže: 25mm; Object Layer Attributes #2, Statická funkce: Ano; Object Layer Attributes #3, Kód prvku: TI06.04.1039; Object Layer Attributes #3, Požární odolnost: A1; Object Layer Attributes #3, Systém kotvení: -; Object Layer Attributes #3, Součinitel prostupu tepla: 0.036; Object Layer Attributes #3, Součinitel difúzního odporu: 1; Object Layer Attributes #3, Způsob spojení vrstev: Lepený + mechanicky kotvený
MINERÁLNÍ VATA | Půdorys 2.NP | EPS 0.02 m, ZELEZOBETONOVÁ KCE 0.25 m, MINERÁLNÍ VATA 0.16 m |  | MINERÁLNÍ VATA |  | 1564HWa0798452870 | m3 | Celá stěna | Nový | Zateplovací systémy | EPS | no | 1564Stě0798452876 | m3 | Stěna |  | 0.43 | 1.178 | 1.038 | 0.375 | 1.327 | 0.372 | 0.579 | 0.95 | NEMSOK - Object Layer Attributes #2, 2D interakce: yes; Object Layer Attributes #2, Status: Nový; Object Layer Attributes #2, Práce: Betonářské práce; Object Layer Attributes #2, Materiál: ZELEZOBETONOVÁ KCE; Object Layer Attributes #2, Allright_Stavebni_dil_ID: 1564Stě0798452875; Object Layer Attributes #2, Jednotka: m3; Object Layer Attributes #2, Název_objektu: Stěna; Object Layer Attributes #3, 2D interakce: yes; Object Layer Attributes #3, Status: Nový; Object Layer Attributes #3, Práce: Zateplovací systémy; Object Layer Attributes #3, Materiál: MINERÁLNÍ VATA; Object Layer Attributes #3, Allright_Stavebni_dil_ID: 1564Stě0798452877; Object Layer Attributes #3, Jednotka: m3; Object Layer Attributes #3, Název_objektu: Stěna; Object Layer Attributes #2, Staticky nosná konstrukce: yes; Object Layer Attributes #3, Staticky nosná konstrukce: no; Object Layer Attributes #1, Kód prvku: TI01.04.1032; Object Layer Attributes #1, Požární odolnost: E; Object Layer Attributes #1, Systém kotvení: -; Object Layer Attributes #1, Součinitel prostupu tepla: 0.039; Object Layer Attributes #1, Součinitel difúzního odporu: 20 - 40; Object Layer Attributes #1, Způsob spojení vrstev: Mechanicky kotvený; Object Layer Attributes #2, Kód prvku: TM02.04.0033; Object Layer Attributes #2, U-hodnota: 0; Object Layer Attributes #2, Požární odolnost: A; Object Layer Attributes #2, Třída pevnosti ocele: B500B; Object Layer Attributes #2, Funkce: Ano; Object Layer Attributes #2, Stupeň vyztužení: 180; Object Layer Attributes #2, Podlaží: 2.NP; Object Layer Attributes #2, Třída pevnosti betonu: C25/30-XC1; Object Layer Attributes #2, Krytí výztuže: 25mm; Object Layer Attributes #2, Statická funkce: Ano; Object Layer Attributes #3, Kód prvku: TI06.04.1040; Object Layer Attributes #3, Požární odolnost: A1; Object Layer Attributes #3, Systém kotvení: -; Object Layer Attributes #3, Součinitel prostupu tepla: 0.036; Object Layer Attributes #3, Součinitel difúzního odporu: 1; Object Layer Attributes #3, Způsob spojení vrstev: Lepený + mechanicky kotvený
MINERÁLNÍ VATA | Půdorys 2.NP | EPS 0.02 m, ZELEZOBETONOVÁ KCE 0.25 m, MINERÁLNÍ VATA 0.16 m |  | MINERÁLNÍ VATA |  | 1564HWa0798455695 | m3 | Celá stěna | Nový | Zateplovací systémy | EPS | no | 1564Stě0798455696 | m3 | Stěna |  | 0.43 | 0.746 | 0.746 | 0.23 | 0.71 | 0.23 | 0.305 | 1.05 | NEMSOK - Object Layer Attributes #2, 2D interakce: yes; Object Layer Attributes #2, Status: Nový; Object Layer Attributes #2, Práce: Betonářské práce; Object Layer Attributes #2, Materiál: ZELEZOBETONOVÁ KCE; Object Layer Attributes #2, Allright_Stavebni_dil_ID: 1564Stě0798455697; Object Layer Attributes #2, Jednotka: m3; Object Layer Attributes #2, Název_objektu: Stěna; Object Layer Attributes #3, 2D interakce: yes; Object Layer Attributes #3, Status: Nový; Object Layer Attributes #3, Práce: Zateplovací systémy; Object Layer Attributes #3, Materiál: MINERÁLNÍ VATA; Object Layer Attributes #3, Allright_Stavebni_dil_ID: 1564Stě0798455698; Object Layer Attributes #3, Jednotka: m3; Object Layer Attributes #3, Název_objektu: Stěna; Object Layer Attributes #2, Staticky nosná konstrukce: yes; Object Layer Attributes #3, Staticky nosná konstrukce: no; Object Layer Attributes #1, Kód prvku: TI01.04.1033; Object Layer Attributes #1, Požární odolnost: E; Object Layer Attributes #1, Systém kotvení: -; Object Layer Attributes #1, Součinitel prostupu tepla: 0.039; Object Layer Attributes #1, Součinitel difúzního odporu: 20 - 40; Object Layer Attributes #1, Způsob spojení vrstev: Mechanicky kotvený; Object Layer Attributes #2, Kód prvku: TM02.04.0034; Object Layer Attributes #2, U-hodnota: 0; Object Layer Attributes #2, Požární odolnost: A; Object Layer Attributes #2, Třída pevnosti ocele: B500B; Object Layer Attributes #2, Funkce: Ano; Object Layer Attributes #2, Stupeň vyztužení: 180; Object Layer Attributes #2, Podlaží: 2.NP; Object Layer Attributes #2, Třída pevnosti betonu: C25/30-XC1; Object Layer Attributes #2, Krytí výztuže: 25mm; Object Layer Attributes #2, Statická funkce: Ano; Object Layer Attributes #3, Kód prvku: TI06.04.1041; Object Layer Attributes #3, Požární odolnost: A1; Object Layer Attributes #3, Systém kotvení: -; Object Layer Attributes #3, Součinitel prostupu tepla: 0.036; Object Layer Attributes #3, Součinitel difúzního odporu: 1; Object Layer Attributes #3, Způsob spojení vrstev: Lepený + mechanicky kotvený
MINERÁLNÍ VATA | Půdorys 2.NP | EPS 0.25 m, ZELEZOBETONOVÁ KCE 0.2 m, MINERÁLNÍ VATA 0.16 m |  | MINERÁLNÍ VATA |  | 1564HWa0798460434 | m3 | Celá stěna | Nový | Zateplovací systémy | EPS | no | 1564Stě0798460438 | m3 | Stěna |  | 0.61 | 4.589 | 4.589 | 2.239 | 3.343 | 2.239 | 2.056 | 1.3 | NEMSOK - Object Layer Attributes #2, 2D interakce: yes; Object Layer Attributes #2, Status: Nový; Object Layer Attributes #2, Práce: Betonářské práce; Object Layer Attributes #2, Materiál: ZELEZOBETONOVÁ KCE; Object Layer Attributes #2, Allright_Stavebni_dil_ID: 1564Stě0798460437; Object Layer Attributes #2, Jednotka: m3; Object Layer Attributes #2, Název_objektu: Stěna; Object Layer Attributes #3, 2D interakce: yes; Object Layer Attributes #3, Status: Nový; Object Layer Attributes #3, Práce: Zateplovací systémy; Object Layer Attributes #3, Materiál: MINERÁLNÍ VATA; Object Layer Attributes #3, Allright_Stavebni_dil_ID: 1564Stě0798460436; Object Layer Attributes #3, Jednotka: m3; Object Layer Attributes #3, Název_objektu: Stěna; Object Layer Attributes #2, Staticky nosná konstrukce: yes; Object Layer Attributes #3, Staticky nosná konstrukce: no; Object Layer Attributes #1, Kód prvku: TI01.04.1034; Object Layer Attributes #1, Požární odolnost: E; Object Layer Attributes #1, Systém kotvení: -; Object Layer Attributes #1, Součinitel prostupu tepla: 0.039; Object Layer Attributes #1, Součinitel difúzního odporu: 20 - 40; Object Layer Attributes #1, Způsob spojení vrstev: Mechanicky kotvený; Object Layer Attributes #2, Kód prvku: TM02.04.0014; Object Layer Attributes #2, U-hodnota: 0; Object Layer Attributes #2, Požární odolnost: A; Object Layer Attributes #2, Třída pevnosti ocele: B500B; Object Layer Attributes #2, Funkce: Ano; Object Layer Attributes #2, Stupeň vyztužení: 120; Object Layer Attributes #2, Podlaží: 2.NP; Object Layer Attributes #2, Třída pevnosti betonu: C25/30-XC1; Object Layer Attributes #2, Krytí výztuže: 25mm; Object Layer Attributes #2, Statická funkce: Ano; Object Layer Attributes #3, Kód prvku: TI06.04.1042; Object Layer Attributes #3, Požární odolnost: A1; Object Layer Attributes #3, Systém kotvení: -; Object Layer Attributes #3, Součinitel prostupu tepla: 0.036; Object Layer Attributes #3, Součinitel difúzního odporu: 1; Object Layer Attributes #3, Způsob spojení vrstev: Lepený + mechanicky kotvený
EPS | Půdorys 2.NP | EPS 0.1 m | 1 | EPS |  | 1564HWa0798460831 | m3 | Celá stěna | Nový | Zateplovací systémy | EPS | no | 1564Stě0798460832 | m3 | Stěna |  | 0.1 | 0.603 | 0.603 | 0.06 | 1.005 | 0.06 | 0.101 | 0.6 | NEMSOK - Object Layer Attributes #1, Kód prvku: TI01.04.1035; Object Layer Attributes #1, Požární odolnost: E; Object Layer Attributes #1, Systém kotvení: -; Object Layer Attributes #1, Součinitel prostupu tepla: 0.039; Object Layer Attributes #1, Součinitel difúzního odporu: 20 - 40; Object Layer Attributes #1, Způsob spojení vrstev: Lepený + mechanicky kotvený
MINERÁLNÍ VATA | Půdorys 2.NP | EPS |  | MINERÁLNÍ VATA |  | 1564HWa0798463970 | m3 | Celá stěna | Nový | Zateplovací systémy | EPS | no | 1564Stě0798463976 | m3 | Stěna |  | 0.27 | 6.195 | 6.179 | 1.104 | 1.85 | 1.104 | 0.442 | 2.95 | NEMSOK - Object Layer Attributes #2, 2D interakce: yes; Object Layer Attributes #2, Status: Nový; Object Layer Attributes #2, Práce: Betonářské práce; Object Layer Attributes #2, Materiál: ZELEZOBETONOVÁ KCE; Object Layer Attributes #2, Allright_Stavebni_dil_ID: 1564Stě0798463975; Object Layer Attributes #2, Jednotka: m3; Object Layer Attributes #2, Název_objektu: Stěna; Object Layer Attributes #2, Staticky nosná konstrukce: yes; Object Layer Attributes #1, Kód prvku: TI01.04.1036; Object Layer Attributes #1, Požární odolnost: E; Object Layer Attributes #1, Systém kotvení: -; Object Layer Attributes #1, Součinitel prostupu tepla: 0.039; Object Layer Attributes #1, Součinitel difúzního odporu: 20 - 40; Object Layer Attributes #1, Způsob spojení vrstev: Mechanicky kotvený; Object Layer Attributes #2, Kód prvku: SN02.04.0001; Object Layer Attributes #2, U-hodnota: 0; Object Layer Attributes #2, Požární odolnost: A; Object Layer Attributes #2, Třída pevnosti ocele: B500B; Object Layer Attributes #2, Funkce: Ano; Object Layer Attributes #2, Stupeň vyztužení: 150; Object Layer Attributes #2, Podlaží: 2.NP; Object Layer Attributes #2, Třída pevnosti betonu: C25/30-XC1; Object Layer Attributes #2, Krytí výztuže: 25mm; Object Layer Attributes #2, Statická funkce: Ano
MINERÁLNÍ VATA | Půdorys 2.NP | EPS 0.02 m, ZELEZOBETONOVÁ KCE 0.25 m, MINERÁLNÍ VATA 0.16 m |  | MINERÁLNÍ VATA |  | 1564HWa0798466168 | m3 | Celá stěna | Nový | Zateplovací systémy | EPS | no | 1564Stě0798466171 | m3 | Stěna |  | 0.43 | 0.665 | 0.665 | 0.197 | 0.697 | 0.197 | 0.301 | 0.95 | NEMSOK - Object Layer Attributes #2, 2D interakce: yes; Object Layer Attributes #2, Status: Nový; Object Layer Attributes #2, Práce: Betonářské práce; Object Layer Attributes #2, Materiál: ZELEZOBETONOVÁ KCE; Object Layer Attributes #2, Allright_Stavebni_dil_ID: 1564Stě0798466172; Object Layer Attributes #2, Jednotka: m3; Object Layer Attributes #2, Název_objektu: Stěna; Object Layer Attributes #3, 2D interakce: yes; Object Layer Attributes #3, Status: Nový; Object Layer Attributes #3, Práce: Zateplovací systémy; Object Layer Attributes #3, Materiál: MINERÁLNÍ VATA; Object Layer Attributes #3, Allright_Stavebni_dil_ID: 1564Stě0798466173; Object Layer Attributes #3, Jednotka: m3; Object Layer Attributes #3, Název_objektu: Stěna; Object Layer Attributes #2, Staticky nosná konstrukce: yes; Object Layer Attributes #3, Staticky nosná konstrukce: no; Object Layer Attributes #1, Kód prvku: TI01.04.1037; Object Layer Attributes #1, Požární odolnost: E; Object Layer Attributes #1, Systém kotvení: -; Object Layer Attributes #1, Součinitel prostupu tepla: 0.039; Object Layer Attributes #1, Součinitel difúzního odporu: 20 - 40; Object Layer Attributes #1, Způsob spojení vrstev: Mechanicky kotvený; Object Layer Attributes #2, Kód prvku: TM02.04.0035; Object Layer Attributes #2, U-hodnota: 0; Object Layer Attributes #2, Požární odolnost: A; Object Layer Attributes #2, Třída pevnosti ocele: B500B; Object Layer Attributes #2, Funkce: Ano; Object Layer Attributes #2, Stupeň vyztužení: 180; Object Layer Attributes #2, Podlaží: 2.NP; Object Layer Attributes #2, Třída pevnosti betonu: C25/30-XC1; Object Layer Attributes #2, Krytí výztuže: 25mm; Object Layer Attributes #2, Statická funkce: Ano; Object Layer Attributes #3, Kód prvku: TI06.04.1043; Object Layer Attributes #3, Požární odolnost: A1; Object Layer Attributes #3, Systém kotvení: -; Object Layer Attributes #3, Součinitel prostupu tepla: 0.036; Object Layer Attributes #3, Součinitel difúzního odporu: 1; Object Layer Attributes #3, Způsob spojení vrstev: Lepený + mechanicky kotvený
MINERÁLNÍ VATA | Půdorys 2.NP | MINERÁLNÍ VATA 0.3 m, ZELEZOBETONOVÁ KCE 0.25 m, MINERÁLNÍ VATA 0.16 m |  | MINERÁLNÍ VATA |  | 1564HWa0798468507 | m3 | Celá stěna | Nový | Zateplovací systémy | MINERÁLNÍ VATA | no | 1564Stě0798468512 | m3 | Stěna |  | 0.71 | 10.287 | 10.287 | 5.419 | 7.817 | 5.419 | 5.588 | 1.27 | NEMSOK - Object Layer Attributes #2, 2D interakce: yes; Object Layer Attributes #2, Status: Nový; Object Layer Attributes #2, Práce: Betonářské práce; Object Layer Attributes #2, Materiál: ZELEZOBETONOVÁ KCE; Object Layer Attributes #2, Allright_Stavebni_dil_ID: 1564Stě0798468513; Object Layer Attributes #2, Jednotka: m3; Object Layer Attributes #2, Název_objektu: Stěna; Object Layer Attributes #3, 2D interakce: yes; Object Layer Attributes #3, Status: Nový; Object Layer Attributes #3, Práce: Zateplovací systémy; Object Layer Attributes #3, Materiál: MINERÁLNÍ VATA; Object Layer Attributes #3, Allright_Stavebni_dil_ID: 1564Stě0798468514; Object Layer Attributes #3, Jednotka: m3; Object Layer Attributes #3, Název_objektu: Stěna; Object Layer Attributes #2, Staticky nosná konstrukce: yes; Object Layer Attributes #3, Staticky nosná konstrukce: no; Object Layer Attributes #1, Kód prvku: TI06.04.0011; Object Layer Attributes #1, Požární odolnost: A1; Object Layer Attributes #1, Systém kotvení: -; Object Layer Attributes #1, Součinitel prostupu tepla: 0.036; Object Layer Attributes #1, Součinitel difúzního odporu: 1; Object Layer Attributes #1, Způsob spojení vrstev: Lepený + mechanicky kotvený; Object Layer Attributes #2, Kód prvku: TM02.04.0036; Object Layer Attributes #2, U-hodnota: 0; Object Layer Attributes #2, Požární odolnost: A; Object Layer Attributes #2, Třída pevnosti ocele: B500B; Object Layer Attributes #2, Funkce: Ano; Object Layer Attributes #2, Stupeň vyztužení: 180; Object Layer Attributes #2, Podlaží: 2.NP; Object Layer Attributes #2, Třída pevnosti betonu: C25/30-XC1; Object Layer Attributes #2, Krytí výztuže: 25mm; Object Layer Attributes #2, Statická funkce: Ano; Object Layer Attributes #3, Kód prvku: TI06.04.1044; Object Layer Attributes #3, Požární odolnost: A1; Object Layer Attributes #3, Systém kotvení: -; Object Layer Attributes #3, Součinitel prostupu tepla: 0.036; Object Layer Attributes #3, Součinitel difúzního odporu: 1; Object Layer Attributes #3, Způsob spojení vrstev: Lepený + mechanicky kotvený
MINERÁLNÍ VATA | Půdorys 2.NP | MINERÁLNÍ VATA 0.3 m, ZELEZOBETONOVÁ KCE 0.25 m, MINERÁLNÍ VATA 0.16 m |  | MINERÁLNÍ VATA |  | 1564HWa0798468585 | m3 | Celá stěna | Nový | Zateplovací systémy | MINERÁLNÍ VATA | no | 1564Stě0798468591 | m3 | Stěna |  | 0.71 | 22.606 | 22.581 | 12.073 | 17.58 | 12.061 | 12.51 | 1.27 | NEMSOK - Object Layer Attributes #2, 2D interakce: yes; Object Layer Attributes #2, Status: Nový; Object Layer Attributes #2, Práce: Betonářské práce; Object Layer Attributes #2, Materiál: ZELEZOBETONOVÁ KCE; Object Layer Attributes #2, Allright_Stavebni_dil_ID: 1564Stě0798468593; Object Layer Attributes #2, Jednotka: m3; Object Layer Attributes #2, Název_objektu: Stěna; Object Layer Attributes #3, 2D interakce: yes; Object Layer Attributes #3, Status: Nový; Object Layer Attributes #3, Práce: Zateplovací systémy; Object Layer Attributes #3, Materiál: MINERÁLNÍ VATA; Object Layer Attributes #3, Allright_Stavebni_dil_ID: 1564Stě0798468592; Object Layer Attributes #3, Jednotka: m3; Object Layer Attributes #3, Název_objektu: Stěna; Object Layer Attributes #2, Staticky nosná konstrukce: yes; Object Layer Attributes #3, Staticky nosná konstrukce: no; Object Layer Attributes #1, Kód prvku: TI06.04.0012; Object Layer Attributes #1, Požární odolnost: A1; Object Layer Attributes #1, Systém kotvení: -; Object Layer Attributes #1, Součinitel prostupu tepla: 0.036; Object Layer Attributes #1, Součinitel difúzního odporu: 1; Object Layer Attributes #1, Způsob spojení vrstev: Lepený + mechanicky kotvený; Object Layer Attributes #2, Kód prvku: TM02.04.0037; Object Layer Attributes #2, U-hodnota: 0; Object Layer Attributes #2, Požární odolnost: A; Object Layer Attributes #2, Třída pevnosti ocele: B500B; Object Layer Attributes #2, Funkce: Ano; Object Layer Attributes #2, Stupeň vyztužení: 180; Object Layer Attributes #2, Podlaží: 2.NP; Object Layer Attributes #2, Třída pevnosti betonu: C25/30-XC1; Object Layer Attributes #2, Krytí výztuže: 25mm; Object Layer Attributes #2, Statická funkce: Ano; Object Layer Attributes #3, Kód prvku: TI06.04.1045; Object Layer Attributes #3, Požární odolnost: A1; Object Layer Attributes #3, Systém kotvení: -; Object Layer Attributes #3, Součinitel prostupu tepla: 0.036; Object Layer Attributes #3, Součinitel difúzního odporu: 1; Object Layer Attributes #3, Způsob spojení vrstev: Lepený + mechanicky kotvený
MINERÁLNÍ VATA | Půdorys 2.NP | MINERÁLNÍ VATA 0.3 m, ZELEZOBETONOVÁ KCE 0.25 m, MINERÁLNÍ VATA 0.16 m |  | MINERÁLNÍ VATA |  | 1564HWa0798450849 | m3 | Celá stěna | Nový | Zateplovací systémy | MINERÁLNÍ VATA | no | 1564Stě0798450850 | m3 | Stěna |  | 0.71 | 13.398 | 13.398 | 7.425 | 11.388 | 7.425 | 8.112 | 1.15 | NEMSOK - Object Layer Attributes #2, 2D interakce: yes; Object Layer Attributes #2, Status: Nový; Object Layer Attributes #2, Práce: Betonářské práce; Object Layer Attributes #2, Materiál: ZELEZOBETONOVÁ KCE; Object Layer Attributes #2, Allright_Stavebni_dil_ID: 1564Stě0798450851; Object Layer Attributes #2, Jednotka: m3; Object Layer Attributes #2, Název_objektu: Stěna; Object Layer Attributes #3, 2D interakce: yes; Object Layer Attributes #3, Status: Nový; Object Layer Attributes #3, Práce: Zateplovací systémy; Object Layer Attributes #3, Materiál: MINERÁLNÍ VATA; Object Layer Attributes #3, Allright_Stavebni_dil_ID: 1564Stě0798450852; Object Layer Attributes #3, Jednotka: m3; Object Layer Attributes #3, Název_objektu: Stěna; Object Layer Attributes #2, Staticky nosná konstrukce: yes; Object Layer Attributes #3, Staticky nosná konstrukce: no; Object Layer Attributes #1, Kód prvku: TI06.04.0005; Object Layer Attributes #1, Požární odolnost: A1; Object Layer Attributes #1, Systém kotvení: -; Object Layer Attributes #1, Součinitel prostupu tepla: 0.036; Object Layer Attributes #1, Součinitel difúzního odporu: 1; Object Layer Attributes #1, Způsob spojení vrstev: Lepený + mechanicky kotvený; Object Layer Attributes #2, Kód prvku: TM02.04.0015; Object Layer Attributes #2, U-hodnota: 0; Object Layer Attributes #2, Požární odolnost: A; Object Layer Attributes #2, Třída pevnosti ocele: B500B; Object Layer Attributes #2, Funkce: Ano; Object Layer Attributes #2, Stupeň vyztužení: 180; Object Layer Attributes #2, Podlaží: 2.NP; Object Layer Attributes #2, Třída pevnosti betonu: C25/30-XC1; Object Layer Attributes #2, Krytí výztuže: 25mm; Object Layer Attributes #2, Statická funkce: Ano; Object Layer Attributes #3, Kód prvku: TI06.04.1022; Object Layer Attributes #3, Požární odolnost: A1; Object Layer Attributes #3, Systém kotvení: -; Object Layer Attributes #3, Součinitel prostupu tepla: 0.036; Object Layer Attributes #3, Součinitel difúzního odporu: 1; Object Layer Attributes #3, Způsob spojení vrstev: Lepený + mechanicky kotvený
ZDIVO Z CDm | Půdorys 3.NP | ZDIVO Z CDm 0.5 m | 1 | ZDIVO Z CDm | A | 1652HWa0000000107 | m3 | Celá stěna | Stávající | Zednické práce | ZDIVO Z CDm | yes | 1652Stě0000000108 | m3 | Stěna | 0 | 0.5 | 17.168 | 17.168 | 8.584 | 5.45 | 8.584 | 2.725 | 3.15
ZDIVO Z CDm | Půdorys 3.NP | ZDIVO Z CDm 0.5 m | 1 | ZDIVO Z CDm | A | 1652HWa0000000117 | m3 | Celá stěna | Stávající | Zednické práce | ZDIVO Z CDm | yes | 1652Stě0000000118 | m3 | Stěna | 0 | 0.5 | 11.025 | 11.025 | 5.512 | 3.5 | 5.512 | 1.75 | 3.15
ZDIVO Z CDm | Půdorys 3.NP | ZDIVO Z CDm 0.125 m |  | ZDIVO Z CDm | A | 1652HWa0000000147 | m3 | Celá stěna | Stávající | Zednické práce | ZDIVO Z CDm | no | 1652Stě0000000148 | m3 | Stěna | 0 | 0.125 | 7.56 | 7.56 | 0.945 | 2.4 | 0.945 | 0.3 | 3.15
ZELEZOBETONOVÁ KCE | Půdorys 3.NP | ZELEZOBETONOVÁ KCE 0.3 m | 1 | ZELEZOBETONOVÁ KCE | A | 1652HWa0798424531 | m3 | Celá stěna | Stávající | Betonářské práce | ZELEZOBETONOVÁ KCE |  | 1652Stě0798426732 | m3 | Stěna | 0 | 0.3 | 3.366 | 3.366 | 1.01 | 1.02 | 1.01 | 0.306 | 3.3
ZELEZOBETONOVÁ KCE | Půdorys 3.NP | ZELEZOBETONOVÁ KCE 0.3 m | 1 | ZELEZOBETONOVÁ KCE | A | 1652HWa0798424540 | m3 | Celá stěna | Stávající | Betonářské práce | ZELEZOBETONOVÁ KCE |  | 1652Stě0798426157 | m3 | Stěna | 0 | 0.3 | 18.81 | 18.81 | 5.643 | 5.7 | 5.643 | 1.71 | 3.3
ZELEZOBETONOVÁ KCE | Půdorys 3.NP | ZELEZOBETONOVÁ KCE 0.32 m | 1 | ZELEZOBETONOVÁ KCE | A | 1652HWa0798424547 | m3 | Celá stěna | Stávající | Betonářské práce | ZELEZOBETONOVÁ KCE |  | 1652Stě0798426721 | m3 | Stěna | 0 | 0.32 | 27.72 | 19.395 | 8.87 | 8.4 | 6.078 | 2.688 | 3.3
ZELEZOBETONOVÁ KCE | Půdorys 3.NP | ZELEZOBETONOVÁ KCE 0.3 m | 1 | ZELEZOBETONOVÁ KCE | A | 1652HWa0798426529 | m3 | Celá stěna | Stávající | Betonářské práce | ZELEZOBETONOVÁ KCE |  | 1652Stě0798426723 | m3 | Stěna | 0 | 0.3 | 3.366 | 3.366 | 1.01 | 1.02 | 1.01 | 0.306 | 3.3
ZELEZOBETONOVÁ KCE | Půdorys 3.NP | ZELEZOBETONOVÁ KCE 0.3 m | 1 | ZELEZOBETONOVÁ KCE | A | 1652HWa0798426604 | m3 | Celá stěna | Stávající | Betonářské práce | ZELEZOBETONOVÁ KCE |  | 1652Stě0798426697 | m3 | Stěna | 0 | 0.3 | 3.366 | 3.366 | 1.01 | 1.02 | 1.01 | 0.306 | 3.3
ZELEZOBETONOVÁ KCE | Půdorys 3.NP | ZELEZOBETONOVÁ KCE 0.3 m | 1 | ZELEZOBETONOVÁ KCE | A | 1652HWa0798426652 | m3 | Celá stěna | Stávající | Betonářské práce | ZELEZOBETONOVÁ KCE |  | 1652Stě0798426689 | m3 | Stěna | 0 | 0.3 | 51.48 | 43.38 | 15.444 | 15.6 | 13.014 | 4.68 | 3.3
ZELEZOBETONOVÁ KCE | Půdorys 3.NP | ZELEZOBETONOVÁ KCE 0.3 m | 1 | ZELEZOBETONOVÁ KCE | A | 1652HWa0798424528 | m3 | Celá stěna | Stávající | Betonářské práce | ZELEZOBETONOVÁ KCE |  | 1652Stě0798426161 | m3 | Stěna | 0 | 0.3 | 3.366 | 3.366 | 1.01 | 1.02 | 1.01 | 0.306 | 3.3
PLYNOSILIKÁT | Půdorys 3.NP | PLYNOSILIKÁT 0.32 m | 1 | PLYNOSILIKÁT | REI 180 | 1652HWa0798431608 | m3 | Celá stěna | Stávající | Zednické práce | PLYNOSILIKÁT |  | 1652Stě0798431674 | m3 | Stěna | 0.541 | 0.32 | 9.504 | 6.804 | 3.041 | 2.88 | 2.135 | 0.922 | 3.3 | Pset_WallCommon - AcousticRating: 48 dB
PLYNOSILIKÁT | Půdorys 3.NP | PLYNOSILIKÁT 0.32 m | 1 | PLYNOSILIKÁT | REI 180 | 1652HWa0798424533 | m3 | Celá stěna | Stávající | Zednické práce | PLYNOSILIKÁT |  | 1652Stě0798426727 | m3 | Stěna | 0.541 | 0.32 | 1.584 | 1.584 | 0.507 | 0.48 | 0.507 | 0.154 | 3.3 | Pset_WallCommon - AcousticRating: 48 dB
PLYNOSILIKÁT | Půdorys 3.NP | PLYNOSILIKÁT 0.32 m |  | PLYNOSILIKÁT | REI 180 | 1652HWa0798431745 | m3 | Celá stěna | Stávající | Zednické práce | PLYNOSILIKÁT |  | 1652Stě0798431801 | m3 | Stěna | 0.541 | 0.32 | 47.854 | 28.642 | 15.313 | 15.69 | 9.409 | 5.021 | 3.05 | Pset_WallCommon - AcousticRating: 48 dB
ZDIVO Z CDm | Půdorys 3.NP | ZDIVO 0.15 m |  | ZDIVO Z CDm | A | 1652HWa0798432066 | m3 | Celá stěna | Stávající | Zednické práce | ZDIVO |  | 1652Stě0798432067 | m3 | Stěna | 0 | 0.15 | 0.45 | 0.45 | 0.068 | 0.45 | 0.068 | 0.068 | 1
ZDIVO Z CDm | Půdorys 3.NP | ZDIVO 0.15 m | 1 | ZDIVO Z CDm | A | 1652HWa0798432093 | m3 | Celá stěna | Stávající | Zednické práce | ZDIVO |  | 1652Stě0798432094 | m3 | Stěna | 0 | 0.15 | 0.45 | 0.45 | 0.068 | 0.45 | 0.068 | 0.068 | 1
ZDIVO Z CDm | Půdorys 3.NP | ZDIVO 0.15 m | 1 | ZDIVO Z CDm | A | 1652HWa0798432081 | m3 | Celá stěna | Stávající | Zednické práce | ZDIVO |  | 1652Stě0798432082 | m3 | Stěna | 0 | 0.15 | 0.45 | 0.45 | 0.068 | 0.45 | 0.068 | 0.068 | 1
ZDIVO Z CDm | Půdorys 3.NP | ZDIVO 0.15 m | 1 | ZDIVO Z CDm | A | 1652HWa0798432071 | m3 | Celá stěna | Stávající | Zednické práce | ZDIVO |  | 1652Stě0798432072 | m3 | Stěna | 0 | 0.15 | 0.45 | 0.45 | 0.068 | 0.45 | 0.068 | 0.068 | 1
ZDIVO Z CDm | Půdorys 3.NP | ZDIVO 0.15 m |  | ZDIVO Z CDm | A | 1652HWa0798432241 | m3 | Celá stěna | Stávající | Zednické práce | ZDIVO |  | 1652Stě0798432251 | m3 | Stěna | 0 | 0.15 | 0.36 | 0.36 | 0.054 | 0.45 | 0.054 | 0.068 | 0.8
ZDIVO Z CDm | Půdorys 3.NP | ZDIVO 0.15 m | 1 | ZDIVO Z CDm | A | 1652HWa0798432242 | m3 | Celá stěna | Stávající | Zednické práce | ZDIVO |  | 1652Stě0798432250 | m3 | Stěna | 0 | 0.15 | 0.36 | 0.36 | 0.054 | 0.45 | 0.054 | 0.068 | 0.8
ZDIVO Z CDm | Půdorys 3.NP | ZDIVO 0.15 m | 1 | ZDIVO Z CDm | A | 1652HWa0798432244 | m3 | Celá stěna | Stávající | Zednické práce | ZDIVO |  | 1652Stě0798432252 | m3 | Stěna | 0 | 0.15 | 0.36 | 0.36 | 0.054 | 0.45 | 0.054 | 0.068 | 0.8
ZDIVO Z CDm | Půdorys 3.NP | ZDIVO 0.15 m | 1 | ZDIVO Z CDm | A | 1652HWa0798432246 | m3 | Celá stěna | Stávající | Zednické práce | ZDIVO |  | 1652Stě0798432248 | m3 | Stěna | 0 | 0.15 | 0.36 | 0.36 | 0.054 | 0.45 | 0.054 | 0.068 | 0.8
ZDIVO Z CDm | Půdorys 3.NP | ZDIVO 0.15 m |  | ZDIVO Z CDm | A | 1652HWa0798432253 | m3 | Celá stěna | Stávající | Zednické práce | ZDIVO |  | 1652Stě0798432263 | m3 | Stěna | 0 | 0.15 | 0.45 | 0.45 | 0.068 | 0.45 | 0.068 | 0.068 | 1
ZDIVO Z CDm | Půdorys 3.NP | ZDIVO 0.15 m | 1 | ZDIVO Z CDm | A | 1652HWa0798432254 | m3 | Celá stěna | Stávající | Zednické práce | ZDIVO |  | 1652Stě0798432262 | m3 | Stěna | 0 | 0.15 | 0.45 | 0.45 | 0.068 | 0.45 | 0.068 | 0.068 | 1
ZDIVO Z CDm | Půdorys 3.NP | ZDIVO 0.15 m | 1 | ZDIVO Z CDm | A | 1652HWa0798432256 | m3 | Celá stěna | Stávající | Zednické práce | ZDIVO |  | 1652Stě0798432264 | m3 | Stěna | 0 | 0.15 | 0.45 | 0.45 | 0.068 | 0.45 | 0.068 | 0.068 | 1
ZDIVO Z CDm | Půdorys 3.NP | ZDIVO 0.15 m | 1 | ZDIVO Z CDm | A | 1652HWa0798432258 | m3 | Celá stěna | Stávající | Zednické práce | ZDIVO |  | 1652Stě0798432260 | m3 | Stěna | 0 | 0.15 | 0.45 | 0.45 | 0.068 | 0.45 | 0.068 | 0.068 | 1
ZDIVO Z CDm | Půdorys 3.NP | ZDIVO 0.15 m |  | ZDIVO Z CDm | A | 1652HWa0798432277 | m3 | Celá stěna | Stávající | Zednické práce | ZDIVO |  | 1652Stě0798432287 | m3 | Stěna | 0 | 0.15 | 0.75 | 0.75 | 0.113 | 0.75 | 0.113 | 0.113 | 1
ZDIVO Z CDm | Půdorys 3.NP | ZDIVO 0.15 m | 1 | ZDIVO Z CDm | A | 1652HWa0798432143 | m3 | Celá stěna | Stávající | Zednické práce | ZDIVO |  | 1652Stě0798432141 | m3 | Stěna | 0 | 0.15 | 0.84 | 0.84 | 0.126 | 1.05 | 0.126 | 0.158 | 0.8
ZDIVO Z CDm | Půdorys 3.NP | ZDIVO 0.15 m |  | ZDIVO Z CDm | A | 1652HWa0798432144 | m3 | Celá stěna | Stávající | Zednické práce | ZDIVO |  | 1652Stě0798432146 | m3 | Stěna | 0 | 0.15 | 0.36 | 0.36 | 0.054 | 0.45 | 0.054 | 0.067 | 0.8
ZDIVO Z CDm | Půdorys 3.NP | ZDIVO 0.15 m | 1 | ZDIVO Z CDm | A | 1652HWa0798432140 | m3 | Celá stěna | Stávající | Zednické práce | ZDIVO |  | 1652Stě0798432138 | m3 | Stěna | 0 | 0.15 | 0.36 | 0.36 | 0.054 | 0.45 | 0.054 | 0.068 | 0.8
ZDIVO Z CDm | Půdorys 3.NP | ZDIVO 0.15 m |  | ZDIVO Z CDm | A | 1652HWa0798432132 | m3 | Celá stěna | Stávající | Zednické práce | ZDIVO |  | 1652Stě0798432134 | m3 | Stěna | 0 | 0.15 | 0.24 | 0.24 | 0.036 | 0.3 | 0.036 | 0.045 | 0.8
ZELEZOBETONOVÁ KCE | Půdorys 3.NP | ZELEZOBETONOVÁ KCE 0.2 m | 1 | ZELEZOBETONOVÁ KCE | A | 1652HWa0798434476 | m3 | Celá stěna | Stávající | Betonářské práce | ZELEZOBETONOVÁ KCE | yes | 1652Stě0798436010 | m3 | Stěna | 0 | 0.2 | 9.15 | 9.15 | 1.83 | 3 | 1.83 | 0.6 | 3.05
ZDIVO Z CDm | Půdorys 3.NP | ZDIVO Z CDm 0.25 m | 1 | ZDIVO Z CDm | A | 1652HWa0798434480 | m3 | Celá stěna | Stávající | Zednické práce | ZDIVO Z CDm | yes | 1652Stě0798436005 | m3 | Stěna | 0 | 0.25 | 15.25 | 8.244 | 3.812 | 5 | 2.061 | 1.25 | 3.05
ZDIVO Z CDm | Půdorys 3.NP | ZDIVO Z CDm 0.35 m | 1 | ZDIVO Z CDm | A | 1652HWa0798435998 | m3 | Celá stěna | Stávající | Zednické práce | ZDIVO Z CDm | yes | 1652Stě0798436012 | m3 | Stěna | 0 | 0.35 | 1.22 | 1.22 | 0.427 | 0.4 | 0.427 | 0.14 | 3.05
ZDIVO Z CDm | Půdorys 3.NP | ZDIVO Z CDm 0.35 m | 1 | ZDIVO Z CDm | A | 1652HWa0798436000 | m3 | Celá stěna | Stávající | Zednické práce | ZDIVO Z CDm | yes | 1652Stě0798436007 | m3 | Stěna | 0 | 0.35 | 1.22 | 1.22 | 0.427 | 0.4 | 0.427 | 0.14 | 3.05
PLYNOSILIKÁT | Půdorys 3.NP | PLYNOSILIKÁT 0.3 m | 1 | PLYNOSILIKÁT | REI 180 | 1652HWa0798426680 | m3 | Celá stěna | Stávající | Zednické práce | PLYNOSILIKÁT |  | 1652Stě0798426691 | m3 | Stěna | 0.541 | 0.3 | 2.706 | 3.036 | 0.812 | 0.82 | 0.812 | 0.246 | 3.3 | Pset_WallCommon - AcousticRating: 48 dB
ZDIVO Z CDm | Půdorys 3.NP | ZDIVO Z CDm 0.125 m | 1 | ZDIVO Z CDm | A | 1652HWa0798437367 | m3 | Celá stěna | Stávající | Zednické práce | ZDIVO Z CDm | yes | 1652Stě0798437368 | m3 | Stěna | 0 | 0.125 | 1.586 | 1.586 | 0.198 | 0.52 | 0.198 | 0.065 | 3.05
ZDIVO Z CDm | Půdorys 3.NP | ZDIVO Z CDm 0.2 m | 1 | ZDIVO Z CDm | A | 1652HWa0798437561 | m3 | Celá stěna | Stávající | Zednické práce | ZDIVO Z CDm |  | 1652Stě0798437570 | m3 | Stěna | 0 | 0.2 | 1.22 | 1.22 | 0.244 | 0.4 | 0.244 | 0.08 | 3.05
ZDIVO Z CDm | Půdorys 3.NP | ZDIVO Z CDm 0.125 m | 1 | ZDIVO Z CDm | A | 1652HWa0798437578 | m3 | Celá stěna | Stávající | Zednické práce | ZDIVO Z CDm |  | 1652Stě0798437572 | m3 | Stěna | 0 | 0.125 | 1.007 | 1.007 | 0.126 | 0.33 | 0.126 | 0.041 | 3.05
ZDIVO Z CDm | Půdorys 3.NP | ZDIVO Z CDm 0.125 m | 1 | ZDIVO Z CDm | A | 1652HWa0798437586 | m3 | Celá stěna | Stávající | Zednické práce | ZDIVO Z CDm | yes | 1652Stě0798437576 | m3 | Stěna | 0 | 0.125 | 3.126 | 3.126 | 0.391 | 1.025 | 0.391 | 0.128 | 3.05
ZELEZOBETONOVÁ KCE | Půdorys 3.NP | ZELEZOBETONOVÁ KCE 0.32 m | 1 | ZELEZOBETONOVÁ KCE | A | 1652HWa0798426071 | m3 | Celá stěna | Stávající | Betonářské práce | ZELEZOBETONOVÁ KCE |  | 1652Stě0798426618 | m3 | Stěna | 0 | 0.32 | 106.776 | 73.44 | 34.168 | 32.356 | 22.899 | 10.354 | 3.3
ZDIVO Z CDm | Půdorys 3.NP | ZDIVO Z CDm 0.2 m | 1 | ZDIVO Z CDm | A | 1652HWa0798438627 | m3 | Celá stěna | Stávající | Zednické práce | ZDIVO Z CDm | yes | 1652Stě0798438634 | m3 | Stěna | 0 | 0.2 | 0.671 | 0.671 | 0.134 | 0.22 | 0.134 | 0.044 | 3.05
ZELEZOBETONOVÁ KCE | Půdorys 3.NP | ZELEZOBETONOVÁ KCE 0.2 m |  | ZELEZOBETONOVÁ KCE | A | 1652HWa0798426081 | m3 | Celá stěna | Stávající | Betonářské práce | ZELEZOBETONOVÁ KCE | yes | 1652Stě0798426368 | m3 | Stěna | 0 | 0.2 | 14.64 | 14.64 | 2.928 | 4.8 | 2.928 | 0.96 | 3.05
ZELEZOBETONOVÁ KCE | Půdorys 3.NP | ZELEZOBETONOVÁ KCE 0.2 m |  | ZELEZOBETONOVÁ KCE | A | 1652HWa0798426085 | m3 | Celá stěna | Stávající | Betonářské práce | ZELEZOBETONOVÁ KCE | yes | 1652Stě0798426708 | m3 | Stěna | 0 | 0.2 | 16.47 | 16.47 | 3.294 | 5.4 | 3.294 | 1.08 | 3.05
ZELEZOBETONOVÁ KCE | Půdorys 3.NP | ZELEZOBETONOVÁ KCE 0.2 m |  | ZELEZOBETONOVÁ KCE | A | 1652HWa0798426068 | m3 | Celá stěna | Stávající | Betonářské práce | ZELEZOBETONOVÁ KCE | yes | 1652Stě0798426372 | m3 | Stěna | 0 | 0.2 | 10.065 | 10.065 | 2.013 | 3.3 | 2.013 | 0.66 | 3.05
ZDIVO Z CDm | Půdorys 3.NP | ZDIVO Z CDm 0.125 m | 1 | ZDIVO Z CDm | A | 1652HWa0798428323 | m3 | Celá stěna | Stávající | Zednické práce | ZDIVO Z CDm | yes | 1652Stě0798428328 | m3 | Stěna | 0 | 0.125 | 14.03 | 14.03 | 1.754 | 4.6 | 1.754 | 0.575 | 3.05
ZDIVO Z CDm | Půdorys 3.NP | ZDIVO Z CDm 0.125 m | 1 | ZDIVO Z CDm | A | 1652HWa0798428315 | m3 | Celá stěna | Stávající | Zednické práce | ZDIVO Z CDm | yes | 1652Stě0798428322 | m3 | Stěna | 0 | 0.125 | 0.61 | 0.61 | 0.076 | 0.2 | 0.076 | 0.025 | 3.05
ZDIVO Z CDm | Půdorys 3.NP | ZDIVO Z CDm 0.125 m | 1 | ZDIVO Z CDm | A | 1652HWa0798428291 | m3 | Celá stěna | Stávající | Zednické práce | ZDIVO Z CDm | yes | 1652Stě0798428330 | m3 | Stěna | 0 | 0.125 | 4.27 | 4.27 | 0.534 | 1.4 | 0.534 | 0.175 | 3.05
ZDIVO Z CDm | Půdorys 3.NP | ZDIVO Z CDm 0.125 m | 1 | ZDIVO Z CDm | A | 1652HWa0798427964 | m3 | Celá stěna | Stávající | Zednické práce | ZDIVO Z CDm | yes | 1652Stě0798427972 | m3 | Stěna | 0 | 0.125 | 2.364 | 2.364 | 0.295 | 0.775 | 0.295 | 0.097 | 3.05
ZDIVO Z CDm | Půdorys 3.NP | ZDIVO Z CDm 0.125 m | 1 | ZDIVO Z CDm | A | 1652HWa0798428249 | m3 | Celá stěna | Stávající | Zednické práce | ZDIVO Z CDm | yes | 1652Stě0798428250 | m3 | Stěna | 0 | 0.125 | 0.762 | 0.763 | 0.095 | 0.25 | 0.095 | 0.031 | 3.05
ZDIVO Z CDm | Půdorys 3.NP | ZDIVO Z CDm 0.125 m | 1 | ZDIVO Z CDm | A | 1652HWa0798437537 | m3 | Celá stěna | Stávající | Zednické práce | ZDIVO Z CDm | yes | 1652Stě0798437538 | m3 | Stěna | 0 | 0.125 | 5.856 | 5.856 | 0.732 | 1.92 | 0.732 | 0.24 | 3.05
ZDIVO Z CDm | Půdorys 3.NP | ZDIVO Z CDm 0.125 m | 1 | ZDIVO Z CDm | A | 1652HWa0798427962 | m3 | Celá stěna | Stávající | Zednické práce | ZDIVO Z CDm | yes | 1652Stě0798427966 | m3 | Stěna | 0 | 0.125 | 4.041 | 3.551 | 0.505 | 1.325 | 0.444 | 0.166 | 3.05
ZDIVO Z CDm | Půdorys 3.NP | ZDIVO Z CDm 0.125 m | 1 | ZDIVO Z CDm | A | 1652HWa0798426094 | m3 | Celá stěna | Stávající | Zednické práce | ZDIVO Z CDm | yes | 1652Stě0798426389 | m3 | Stěna | 0 | 0.125 | 1.525 | 1.525 | 0.191 | 0.5 | 0.191 | 0.062 | 3.05
ZDIVO Z CDm | Půdorys 3.NP | ZDIVO Z CDm 0.125 m | 1 | ZDIVO Z CDm | A | 1652HWa0798428289 | m3 | Celá stěna | Stávající | Zednické práce | ZDIVO Z CDm | yes | 1652Stě0798428320 | m3 | Stěna | 0 | 0.125 | 10.065 | 10.065 | 1.258 | 3.3 | 1.258 | 0.412 | 3.05
ZDIVO Z CDm | Půdorys 3.NP | ZDIVO Z CDm 0.125 m | 1 | ZDIVO Z CDm | A | 1652HWa0798428290 | m3 | Celá stěna | Stávající | Zednické práce | ZDIVO Z CDm | yes | 1652Stě0798428332 | m3 | Stěna | 0 | 0.125 | 7.091 | 7.091 | 0.886 | 2.325 | 0.886 | 0.291 | 3.05
ZDIVO Z CDm | Půdorys 3.NP | ZDIVO Z CDm 0.125 m | 1 | ZDIVO Z CDm | A | 1652HWa0798437527 | m3 | Celá stěna | Stávající | Zednické práce | ZDIVO Z CDm | yes | 1652Stě0798437528 | m3 | Stěna | 0 | 0.125 | 1.525 | 1.525 | 0.191 | 0.5 | 0.191 | 0.063 | 3.05
ZDIVO Z CDm | Půdorys 3.NP | ZDIVO Z CDm 0.125 m | 1 | ZDIVO Z CDm | A | 1652HWa0798428292 | m3 | Celá stěna | Stávající | Zednické práce | ZDIVO Z CDm | yes | 1652Stě0798428326 | m3 | Stěna | 0 | 0.125 | 11.132 | 8.002 | 1.392 | 3.65 | 1 | 0.456 | 3.05
ZDIVO Z CDm | Půdorys 3.NP | ZDIVO Z CDm 0.4 m |  | ZDIVO Z CDm | A | 1652HWa0798437559 | m3 | Celá stěna | Stávající | Zednické práce | ZDIVO Z CDm |  | 1652Stě0798437568 | m3 | Stěna | 0 | 0.4 | 2.196 | 2.196 | 0.878 | 0.72 | 0.878 | 0.288 | 3.05
ZELEZOBETONOVÁ KCE | Půdorys 3.NP | ZELEZOBETONOVÁ KCE 0.2 m |  | ZELEZOBETONOVÁ KCE | A | 1652HWa0798426083 | m3 | Celá stěna | Stávající | Betonářské práce | ZELEZOBETONOVÁ KCE |  | 1652Stě0798426144 | m3 | Stěna | 0 | 0.2 | 4.575 | 4.575 | 0.915 | 1.5 | 0.915 | 0.3 | 3.05
ZELEZOBETONOVÁ KCE | Půdorys 3.NP | ZELEZOBETONOVÁ KCE 0.2 m |  | ZELEZOBETONOVÁ KCE | A | 1652HWa0798438735 | m3 | Celá stěna | Stávající | Betonářské práce | ZELEZOBETONOVÁ KCE |  | 1652Stě0798438737 | m3 | Stěna | 0 | 0.2 | 14.64 | 14.64 | 2.928 | 4.8 | 2.928 | 0.96 | 3.05
ZELEZOBETONOVÁ KCE | Půdorys 3.NP | ZELEZOBETONOVÁ KCE 0.2 m |  | ZELEZOBETONOVÁ KCE | A | 1652HWa0798424551 | m3 | Celá stěna | Stávající | Betonářské práce | ZELEZOBETONOVÁ KCE |  | 1652Stě0798426385 | m3 | Stěna | 0 | 0.2 | 14.64 | 14.64 | 2.928 | 4.8 | 2.928 | 0.96 | 3.05
ZELEZOBETONOVÁ KCE | Půdorys 3.NP | ZELEZOBETONOVÁ KCE 0.2 m |  | ZELEZOBETONOVÁ KCE | A | 1652HWa0798438724 | m3 | Celá stěna | Stávající | Betonářské práce | ZELEZOBETONOVÁ KCE |  | 1652Stě0798438726 | m3 | Stěna | 0 | 0.2 | 5.795 | 5.795 | 1.159 | 1.9 | 1.159 | 0.38 | 3.05
ZELEZOBETONOVÁ KCE | Půdorys 3.NP | ZELEZOBETONOVÁ KCE 0.2 m |  | ZELEZOBETONOVÁ KCE | A | 1652HWa0798426079 | m3 | Celá stěna | Stávající | Betonářské práce | ZELEZOBETONOVÁ KCE |  | 1652Stě0798426148 | m3 | Stěna | 0 | 0.2 | 5.795 | 5.795 | 1.159 | 1.9 | 1.159 | 0.38 | 3.05
ZDIVO Z CDm | Půdorys 3.NP | ZDIVO Z CDm 0.1 m | 1 | ZDIVO Z CDm | A | 1652HWa0798440156 | m3 | Celá stěna | Stávající | Zednické práce | ZDIVO Z CDm | yes | 1652Stě0798440157 | m3 | Stěna | 0 | 0.1 | 0.839 | 0.839 | 0.084 | 0.275 | 0.084 | 0.027 | 3.05
ZDIVO Z CDm | Půdorys 3.NP | ZDIVO Z CDm 0.125 m | 1 | ZDIVO Z CDm | A | 1652HWa0798437584 | m3 | Celá stěna | Stávající | Zednické práce | ZDIVO Z CDm | yes | 1652Stě0798437620 | m3 | Stěna | 0 | 0.125 | 1.22 | 1.22 | 0.152 | 0.4 | 0.152 | 0.05 | 3.05
ZDIVO Z CDm | Půdorys 3.NP | ZDIVO Z CDm 0.125 m | 1 | ZDIVO Z CDm | A | 1652HWa0798437610 | m3 | Celá stěna | Stávající | Zednické práce | ZDIVO Z CDm | yes | 1652Stě0798437618 | m3 | Stěna | 0 | 0.125 | 41.861 | 38.73 | 5.233 | 13.725 | 4.841 | 1.716 | 3.05
ZDIVO Z CDm | Půdorys 3.NP | ZDIVO Z CDm 0.1 m | 1 | ZDIVO Z CDm | A | 1652HWa0798431966 | m3 | Celá stěna | Stávající | Zednické práce | ZDIVO Z CDm | yes | 1652Stě0798431979 | m3 | Stěna | 0 | 0.125 | 1.281 | 1.525 | 0.16 | 0.42 | 0.16 | 0.052 | 3.05
ZDIVO Z CDm | Půdorys 3.NP | ZDIVO Z CDm 0.125 m | 1 | ZDIVO Z CDm | A | 1652HWa0798437494 | m3 | Celá stěna | Stávající | Zednické práce | ZDIVO Z CDm | yes | 1652Stě0798437495 | m3 | Stěna | 0 | 0.125 | 1.525 | 1.525 | 0.191 | 0.5 | 0.191 | 0.063 | 3.05
ZDIVO Z CDm | Půdorys 3.NP | ZDIVO Z CDm 0.125 m | 1 | ZDIVO Z CDm | A | 1652HWa0798437504 | m3 | Celá stěna | Stávající | Zednické práce | ZDIVO Z CDm | yes | 1652Stě0798437505 | m3 | Stěna | 0 | 0.125 | 12.017 | 10.081 | 1.502 | 3.94 | 1.199 | 0.493 | 3.05
ZELEZOBETONOVÁ KCE | Půdorys 3.NP | ZELEZOBETONOVÁ KCE 0.2 m | 1 | ZELEZOBETONOVÁ KCE | A | 1652HWa0798424552 | m3 | Celá stěna | Stávající | Betonářské práce | ZELEZOBETONOVÁ KCE | yes | 1652Stě0798426140 | m3 | Stěna | 0 | 0.2 | 10.98 | 10.98 | 2.196 | 3.6 | 2.196 | 0.72 | 3.05
ZELEZOBETONOVÁ KCE | Půdorys 3.NP | ZELEZOBETONOVÁ KCE 0.2 m | 1 | ZELEZOBETONOVÁ KCE | A | 1652HWa0798426066 | m3 | Celá stěna | Stávající | Betonářské práce | ZELEZOBETONOVÁ KCE | yes | 1652Stě0798426362 | m3 | Stěna | 0 | 0.2 | 10.98 | 10.98 | 2.196 | 3.6 | 2.196 | 0.72 | 3.05
ZELEZOBETONOVÁ KCE | Půdorys 3.NP | ZELEZOBETONOVÁ KCE 0.2 m | 1 | ZELEZOBETONOVÁ KCE | A | 1652HWa0798438782 | m3 | Celá stěna | Stávající | Betonářské práce | ZELEZOBETONOVÁ KCE | yes | 1652Stě0798438784 | m3 | Stěna | 0 | 0.2 | 12.2 | 12.2 | 2.44 | 4 | 2.44 | 0.8 | 3.05
ZELEZOBETONOVÁ KCE | Půdorys 3.NP | ZELEZOBETONOVÁ KCE 0.3 m | 1 | ZELEZOBETONOVÁ KCE | A | 1652HWa0798424529 | m3 | Celá stěna | Stávající | Betonářské práce | ZELEZOBETONOVÁ KCE |  | 1652Stě0798426730 | m3 | Stěna | 0 | 0.3 | 3.465 | 3.465 | 1.04 | 1.05 | 1.04 | 0.315 | 3.3
ZELEZOBETONOVÁ KCE | Půdorys 3.NP | ZELEZOBETONOVÁ KCE 0.3 m | 1 | ZELEZOBETONOVÁ KCE | A | 1652HWa0798424546 | m3 | Celá stěna | Stávající | Betonářské práce | ZELEZOBETONOVÁ KCE |  | 1652Stě0798426811 | m3 | Stěna | 0 | 0.3 | 3.465 | 3.465 | 1.04 | 1.05 | 1.04 | 0.315 | 3.3
ZELEZOBETONOVÁ KCE | Půdorys 3.NP | ZELEZOBETONOVÁ KCE 0.3 m | 1 | ZELEZOBETONOVÁ KCE | A | 1652HWa0798426636 | m3 | Celá stěna | Stávající | Betonářské práce | ZELEZOBETONOVÁ KCE |  | 1652Stě0798426753 | m3 | Stěna | 0 | 0.3 | 3.366 | 3.366 | 1.01 | 1.02 | 1.01 | 0.306 | 3.3
ZELEZOBETONOVÁ KCE | Půdorys 3.NP | ZELEZOBETONOVÁ KCE 0.3 m | 1 | ZELEZOBETONOVÁ KCE | A | 1652HWa0798426795 | m3 | Celá stěna | Stávající | Betonářské práce | ZELEZOBETONOVÁ KCE | no | 1652Stě0798426801 | m3 | Stěna | 0 | 0.3 | 3.366 | 3.366 | 1.01 | 1.02 | 1.01 | 0.306 | 3.3
PLYNOSILIKÁT | Půdorys 3.NP | PLYNOSILIKÁT 0.32 m | 1 | PLYNOSILIKÁT | REI 180 | 1652HWa0798426734 | m3 | Celá stěna | Stávající | Zednické práce | PLYNOSILIKÁT | no | 1652Stě0798426788 | m3 | Stěna | 0.541 | 0.32 | 51.48 | 21.88 | 16.474 | 15.6 | 7.002 | 4.992 | 3.3 | Pset_WallCommon - AcousticRating: 48 dB
ZELEZOBETONOVÁ KCE | Půdorys 3.NP | ZELEZOBETONOVÁ KCE 0.2 m | 1 | ZELEZOBETONOVÁ KCE | A | 1652HWa0798426063 | m3 | Celá stěna | Stávající | Betonářské práce | ZELEZOBETONOVÁ KCE | yes | 1652Stě0798426360 | m3 | Stěna | 0 | 0.2 | 15.25 | 15.25 | 3.05 | 5 | 3.05 | 1 | 3.05
ZELEZOBETONOVÁ KCE | Půdorys 3.NP | ZELEZOBETONOVÁ KCE 0.3 m | 1 | ZELEZOBETONOVÁ KCE | A | 1652HWa0798424530 | m3 | Celá stěna | Stávající | Betonářské práce | ZELEZOBETONOVÁ KCE |  | 1652Stě0798426164 | m3 | Stěna | 0 | 0.3 | 18.645 | 18.645 | 5.594 | 5.65 | 5.594 | 1.695 | 3.3
ZDIVO Z CDm | Půdorys 3.NP | ZDIVO Z CDm 0.48 m | 1 | ZDIVO Z CDm | A | 1652HWa0798440622 | m3 | Celá stěna | Stávající | Zednické práce | ZDIVO Z CDm |  | 1652Stě0798440626 | m3 | Stěna | 0 | 0.269 | 1.584 | 1.584 | 0.426 | 0.48 | 0.426 | 0.129 | 3.3
ZDIVO Z CDm | Půdorys 3.NP | ZDIVO Z CDm 0.48 m | 1 | ZDIVO Z CDm | A | 1652HWa0798440627 | m3 | Celá stěna | Stávající | Zednické práce | ZDIVO Z CDm |  | 1652Stě0798440631 | m3 | Stěna | 0 | 0.48 | 1.444 | 1.32 | 0.693 | 0.438 | 0.693 | 0.21 | 3.3
ZDIVO Z CDm | Půdorys 3.NP | ZDIVO 0.15 m | 1 | ZDIVO Z CDm | A | 1652HWa0798432282 | m3 | Celá stěna | Stávající | Zednické práce | ZDIVO |  | 1652Stě0798432284 | m3 | Stěna | 0 | 0.15 | 0.9 | 0.9 | 0.135 | 0.9 | 0.135 | 0.135 | 1
ZDIVO Z CDm | Půdorys 3.NP | ZDIVO 0.15 m | 1 | ZDIVO Z CDm | A | 1652HWa0798432280 | m3 | Celá stěna | Stávající | Zednické práce | ZDIVO |  | 1652Stě0798432288 | m3 | Stěna | 0 | 0.15 | 0.75 | 0.75 | 0.113 | 0.75 | 0.113 | 0.113 | 1
ZELEZOBETONOVÁ KCE | Půdorys 3.NP | ZELEZOBETONOVÁ KCE 0.2 m |  | ZELEZOBETONOVÁ KCE | A | 1652HWa0798426503 | m3 | Celá stěna | Stávající | Betonářské práce | ZELEZOBETONOVÁ KCE | yes | 1652Stě0798426677 | m3 | Stěna | 0 | 0.2 | 23.79 | 23.79 | 4.758 | 7.8 | 4.758 | 1.56 | 3.05
ZELEZOBETONOVÁ KCE | Půdorys 3.NP | EPS 0.1 m, ZELEZOBETONOVÁ KCE 0.3 m | 1 | ZELEZOBETONOVÁ KCE | A | 1652HWa0798426630 | m3 | Celá stěna | Stávající | Zateplovací systémy | EPS |  | 1652Stě0798426683 | m2 | Stěna | 0 | 0.4 | 27.39 | 27.39 | 10.956 | 8.3 | 10.956 | 3.32 | 3.3 | NEMSOK - Object Layer Attributes #2, 2D interakce: yes; Object Layer Attributes #2, Status: Stávající; Object Layer Attributes #2, Práce: Betonářské práce; Object Layer Attributes #2, Materiál: ZELEZOBETONOVÁ KCE; Object Layer Attributes #2, Allright_Stavebni_dil_ID: 1652Stě0798441371; Object Layer Attributes #2, Jednotka: m3; Object Layer Attributes #2, Název_objektu: Stěna
ZDIVO Z CDm | Půdorys 3.NP | ZDIVO Z CDm 0.125 m | 1 | ZDIVO Z CDm | A | 1652HWa0798437580 | m3 | Celá stěna | Stávající | Zednické práce | ZDIVO Z CDm |  | 1652Stě0798437574 | m3 | Stěna | 0 | 0.125 | 0.915 | 0.915 | 0.114 | 0.3 | 0.114 | 0.037 | 3.05
ZDIVO Z CDm | Půdorys 3.NP | ZDIVO Z CDm 0.22 m |  | ZDIVO Z CDm | A | 1652HWa0798437563 | m3 | Celá stěna | Stávající | Zednické práce | ZDIVO Z CDm |  | 1652Stě0798437566 | m3 | Stěna | 0 | 0.22 | 2.821 | 2.821 | 0.621 | 0.925 | 0.621 | 0.203 | 3.05
ZELEZOBETONOVÁ KCE | Půdorys 3.NP | ZELEZOBETONOVÁ KCE 0.3 m | 1 | ZELEZOBETONOVÁ KCE | A | 1652HWa0798426566 | m3 | Celá stěna | Stávající | Betonářské práce | ZELEZOBETONOVÁ KCE |  | 1652Stě0798426635 | m3 | Stěna | 0 | 0.3 | 3.96 | 3.96 | 1.188 | 1.2 | 1.188 | 0.36 | 3.3
ZDIVO Z CDm | Půdorys 3.NP | EPS 0.1 m, ZDIVO Z CDm 0.3 m | 1 | ZDIVO Z CDm | A | 1652HWa0798426622 | m3 | Celá stěna | Stávající | Zateplovací systémy | EPS |  | 1652Stě0798426701 | m2 | Stěna | 0 | 0.4 | 2.987 | 2.987 | 0.898 | 0.755 | 0.898 | 0.272 | 3.3 | NEMSOK - Object Layer Attributes #2, 2D interakce: yes; Object Layer Attributes #2, Status: Stávající; Object Layer Attributes #2, Práce: Zednické práce; Object Layer Attributes #2, Materiál: ZDIVO Z CDm; Object Layer Attributes #2, Allright_Stavebni_dil_ID: 1652Stě0798441803; Object Layer Attributes #2, Jednotka: m3; Object Layer Attributes #2, Název_objektu: Stěna
ZDIVO Z CDm | Půdorys 3.NP | ZDIVO Z CDm 0.125 m |  | ZDIVO Z CDm | A | 1652HWa0798440848 | m3 | Celá stěna | Stávající | Zednické práce | ZDIVO Z CDm | no | 1652Stě0798440855 | m3 | Stěna | 0 | 0.125 | 4.96 | 4.96 | 0.62 | 1.6 | 0.62 | 0.2 | 3.1
ZDIVO Z CDm | Půdorys 3.NP | ZDIVO Z CDm 0.125 m |  | ZDIVO Z CDm | A | 1652HWa0798440878 | m3 | Celá stěna | Stávající | Zednické práce | ZDIVO Z CDm | no | 1652Stě0798440879 | m3 | Stěna | 0 | 0.125 | 0.93 | 0.93 | 0.116 | 0.3 | 0.116 | 0.037 | 3.1
ZDIVO Z CDm | Půdorys 3.NP | ZDIVO Z CDm 0.125 m |  | ZDIVO Z CDm | A | 1652HWa0798440863 | m3 | Celá stěna | Stávající | Zednické práce | ZDIVO Z CDm | no | 1652Stě0798440864 | m3 | Stěna | 0 | 0.125 | 1.317 | 1.318 | 0.165 | 0.425 | 0.165 | 0.053 | 3.1
YTONG 375 | Půdorys 3.NP | NEOVĚŘENO 0.375 m |  | YTONG 375 | REI 180 | 1652HWa0798441341 | m3 | Celá stěna | Stávající |  | NEOVĚŘENO | no | 1652Stě0798441343 | m3 | Stěna | 0.442 | 0.375 | 3.715 | 3.715 | 1.393 | 1.21 | 1.393 | 0.454 | 3.07 | Pset_WallCommon - AcousticRating: 49 dB
YTONG 375 | Půdorys 3.NP | NEOVĚŘENO 0.375 m |  | YTONG 375 | REI 180 | 1652HWa0798432453 | m3 | Celá stěna | Stávající |  | NEOVĚŘENO | no | 1652Stě0798432454 | m3 | Stěna | 0.442 | 0.375 | 3.509 | 3.509 | 1.316 | 1.21 | 1.316 | 0.454 | 2.9 | Pset_WallCommon - AcousticRating: 49 dB
ZDIVO Z CDm | Půdorys 3.NP | ZDIVO Z CDm 0.125 m | 1 | ZDIVO Z CDm | A | 1652HWa0798442765 | m3 | Celá stěna | Stávající | Zednické práce | ZDIVO Z CDm | yes | 1652Stě0798442802 | m3 | Stěna | 0 | 0.125 | 5.109 | 4.389 | 0.639 | 1.675 | 0.549 | 0.209 | 3.05
ZDIVO Z CDm | Půdorys 3.NP | ZDIVO Z CDm 0.125 m | 1 | ZDIVO Z CDm | A | 1652HWa0798442768 | m3 | Celá stěna | Stávající | Zednické práce | ZDIVO Z CDm | yes | 1652Stě0798442775 | m3 | Stěna | 0 | 0.125 | 3.965 | 3.965 | 0.496 | 1.3 | 0.496 | 0.162 | 3.05
ZDIVO Z CDm | Půdorys 3.NP | ZDIVO Z CDm 0.25 m | 1 | ZDIVO Z CDm | A | 1652HWa0798442770 | m3 | Celá stěna | Stávající | Zednické práce | ZDIVO Z CDm | yes | 1652Stě0798442778 | m3 | Stěna | 0 | 0.25 | 10.065 | 10.065 | 2.516 | 3.3 | 2.516 | 0.825 | 3.05
ZDIVO Z CDm | Půdorys 3.NP | ZDIVO Z CDm 0.125 m | 1 | ZDIVO Z CDm | A | 1652HWa0798442771 | m3 | Celá stěna | Stávající | Zednické práce | ZDIVO Z CDm | yes | 1652Stě0798442788 | m3 | Stěna | 0 | 0.125 | 3.965 | 3.965 | 0.496 | 1.3 | 0.496 | 0.162 | 3.05
ZDIVO Z CDm | Půdorys 3.NP | ZDIVO Z CDm 0.125 m | 1 | ZDIVO Z CDm | A | 1652HWa0798442767 | m3 | Celá stěna | Stávající | Zednické práce | ZDIVO Z CDm | yes | 1652Stě0798442780 | m3 | Stěna | 0 | 0.125 | 10.065 | 10.065 | 1.258 | 3.3 | 1.258 | 0.413 | 3.05
ZELEZOBETONOVÁ KCE | Půdorys 3.NP | EPS 0.1 m, ZELEZOBETONOVÁ KCE 0.3 m | 1 | ZELEZOBETONOVÁ KCE | A | 1652HWa0798424544 | m3 | Celá stěna | Stávající | Zateplovací systémy | EPS | no | 1652Stě0798426358 | m2 | Stěna | 0 | 0.4 | 11.814 | 11.814 | 4.448 | 3.44 | 4.448 | 1.348 | 3.3 | NEMSOK - Object Layer Attributes #2, 2D interakce: yes; Object Layer Attributes #2, Status: Stávající; Object Layer Attributes #2, Práce: Betonářské práce; Object Layer Attributes #2, Materiál: ZELEZOBETONOVÁ KCE; Object Layer Attributes #2, Allright_Stavebni_dil_ID: 1652Stě0798442919; Object Layer Attributes #2, Jednotka: m3; Object Layer Attributes #2, Název_objektu: Stěna; Object Layer Attributes #2, Staticky nosná konstrukce: no
ZELEZOBETONOVÁ KCE | Půdorys 3.NP | EPS 0.1 m, ZELEZOBETONOVÁ KCE 0.3 m | 1 | ZELEZOBETONOVÁ KCE | A | 1652HWa0798424535 | m3 | Celá stěna | Stávající | Zateplovací systémy | EPS | no | 1652Stě0798426150 | m2 | Stěna | 0 | 0.4 | 11.814 | 11.814 | 4.448 | 3.44 | 4.448 | 1.348 | 3.3 | NEMSOK - Object Layer Attributes #2, 2D interakce: yes; Object Layer Attributes #2, Status: Stávající; Object Layer Attributes #2, Práce: Betonářské práce; Object Layer Attributes #2, Materiál: ZELEZOBETONOVÁ KCE; Object Layer Attributes #2, Allright_Stavebni_dil_ID: 1652Stě0798442962; Object Layer Attributes #2, Jednotka: m3; Object Layer Attributes #2, Název_objektu: Stěna; Object Layer Attributes #2, Staticky nosná konstrukce: no
ZELEZOBETONOVÁ KCE | Půdorys 3.NP | EPS 0.1 m, ZELEZOBETONOVÁ KCE 0.3 m | 1 | ZELEZOBETONOVÁ KCE | A | 1652HWa0798424537 | m3 | Celá stěna | Stávající | Zateplovací systémy | EPS | no | 1652Stě0798426563 | m2 | Stěna | 0 | 0.4 | 10.758 | 8.752 | 4.006 | 3.11 | 3.159 | 1.214 | 3.3 | NEMSOK - Object Layer Attributes #2, 2D interakce: yes; Object Layer Attributes #2, Status: Stávající; Object Layer Attributes #2, Práce: Betonářské práce; Object Layer Attributes #2, Materiál: ZELEZOBETONOVÁ KCE; Object Layer Attributes #2, Allright_Stavebni_dil_ID: 1652Stě0798443007; Object Layer Attributes #2, Jednotka: m3; Object Layer Attributes #2, Název_objektu: Stěna; Object Layer Attributes #2, Staticky nosná konstrukce: no
ZELEZOBETONOVÁ KCE | Půdorys 3.NP | EPS 0.15 m, ZELEZOBETONOVÁ KCE 0.3 m | 1 | ZELEZOBETONOVÁ KCE | A | 1652HWa0798443759 | m3 | Celá stěna | Stávající | Zateplovací systémy | EPS | no | 1652Stě0798443782 | m2 | Stěna | 0 | 0.45 | 26.576 | 26.528 | 11.946 | 8.047 | 11.923 | 3.62 | 3.3 | NEMSOK - Object Layer Attributes #2, 2D interakce: yes; Object Layer Attributes #2, Status: Stávající; Object Layer Attributes #2, Práce: Betonářské práce; Object Layer Attributes #2, Materiál: ZELEZOBETONOVÁ KCE; Object Layer Attributes #2, Allright_Stavebni_dil_ID: 1652Stě0798443781; Object Layer Attributes #2, Jednotka: m3; Object Layer Attributes #2, Název_objektu: Stěna; Object Layer Attributes #2, Staticky nosná konstrukce: no
ZELEZOBETONOVÁ KCE | Půdorys 3.NP | EPS 0.1 m, ZELEZOBETONOVÁ KCE 0.3 m | 1 | ZELEZOBETONOVÁ KCE | A | 1652HWa0798444223 | m3 | Celá stěna | Stávající | Zateplovací systémy | EPS | no | 1652Stě0798444236 | m2 | Stěna | 0 | 0.4 | 8.91 | 6.411 | 3.267 | 2.55 | 2.187 | 0.99 | 3.3 | NEMSOK - Object Layer Attributes #2, 2D interakce: yes; Object Layer Attributes #2, Status: Stávající; Object Layer Attributes #2, Práce: Betonářské práce; Object Layer Attributes #2, Materiál: ZELEZOBETONOVÁ KCE; Object Layer Attributes #2, Allright_Stavebni_dil_ID: 1652Stě0798444235; Object Layer Attributes #2, Jednotka: m3; Object Layer Attributes #2, Název_objektu: Stěna; Object Layer Attributes #2, Staticky nosná konstrukce: no
ZDIVO Z CDm | Půdorys 3.NP | EPS 0.1 m, ZDIVO Z CDm 0.5 m |  | ZDIVO Z CDm | A | 1652HWa0000000058 | m3 | Celá stěna | Stávající | Zateplovací systémy | EPS | no | 1652Stě0000000059 | m2 | Stěna | 0 | 0.6 | 24.48 | 24.48 | 14.418 | 7.4 | 14.418 | 4.52 | 3.4 | NEMSOK - Object Layer Attributes #2, 2D interakce: yes; Object Layer Attributes #2, Status: Stávající; Object Layer Attributes #2, Práce: Zednické práce; Object Layer Attributes #2, Materiál: ZDIVO Z CDm; Object Layer Attributes #2, Allright_Stavebni_dil_ID: 1652Stě0798444609; Object Layer Attributes #2, Jednotka: m3; Object Layer Attributes #2, Název_objektu: Stěna; Object Layer Attributes #2, Staticky nosná konstrukce: yes
ZDIVO Z CDm | Půdorys 3.NP | EPS 0.1 m, ZDIVO Z CDm 0.5 m | 1 | ZDIVO Z CDm | A | 1652HWa0000000004 | m3 | Celá stěna | Stávající | Zateplovací systémy | EPS | no | 1652Stě0000000005 | m2 | Stěna | 0 | 0.6 | 29.41 | 29.41 | 15.62 | 8.35 | 15.62 | 4.89 | 3.4 | NEMSOK - Object Layer Attributes #2, 2D interakce: yes; Object Layer Attributes #2, Status: Stávající; Object Layer Attributes #2, Práce: Zednické práce; Object Layer Attributes #2, Materiál: ZDIVO Z CDm; Object Layer Attributes #2, Allright_Stavebni_dil_ID: 1652Stě0798444689; Object Layer Attributes #2, Jednotka: m3; Object Layer Attributes #2, Název_objektu: Stěna; Object Layer Attributes #2, Staticky nosná konstrukce: yes
ZDIVO Z CDm | Půdorys 3.NP | EPS 0.1 m, ZDIVO Z CDm 0.5 m | 1 | ZDIVO Z CDm | A | 1652HWa0000000036 | m3 | Celá stěna | Stávající | Zateplovací systémy | EPS | no | 1652Stě0000000037 | m2 | Stěna | 0 | 0.6 | 11.9 | 11.9 | 5.757 | 3.2 | 5.757 | 1.8 | 3.4 | NEMSOK - Object Layer Attributes #2, 2D interakce: yes; Object Layer Attributes #2, Status: Stávající; Object Layer Attributes #2, Práce: Zednické práce; Object Layer Attributes #2, Materiál: ZDIVO Z CDm; Object Layer Attributes #2, Allright_Stavebni_dil_ID: 1652Stě0798444736; Object Layer Attributes #2, Jednotka: m3; Object Layer Attributes #2, Název_objektu: Stěna; Object Layer Attributes #2, Staticky nosná konstrukce: yes
ZDIVO Z CDm | Půdorys 3.NP | ZDIVO Z CDm 0.5 m | 1 | ZDIVO Z CDm | A | 1652HWa0798444783 | m3 | Celá stěna | Stávající | Zednické práce | ZDIVO Z CDm | yes | 1652Stě0798444791 | m3 | Stěna | 0 | 0.5 | 15.593 | 10.211 | 7.796 | 4.95 | 5.105 | 2.475 | 3.15
ZDIVO Z CDm | Půdorys 3.NP | EPS 0.1 m, ZDIVO Z CDm 0.5 m | 1 | ZDIVO Z CDm | A | 1652HWa0798422029 | m3 | Celá stěna | Stávající | Zateplovací systémy | EPS | no | 1652Stě0798422030 | m2 | Stěna | 0 | 0.6 | 2.72 | 2.72 | 1.532 | 0.8 | 1.532 | 0.48 | 3.4 | NEMSOK - Object Layer Attributes #2, 2D interakce: yes; Object Layer Attributes #2, Status: Stávající; Object Layer Attributes #2, Práce: Zednické práce; Object Layer Attributes #2, Materiál: ZDIVO Z CDm; Object Layer Attributes #2, Allright_Stavebni_dil_ID: 1652Stě0798444822; Object Layer Attributes #2, Jednotka: m3; Object Layer Attributes #2, Název_objektu: Stěna; Object Layer Attributes #2, Staticky nosná konstrukce: yes
ZDIVO Z CDm | Půdorys 3.NP | ZDIVO Z CDm 0.5 m |  | ZDIVO Z CDm | A | 1652HWa0798444991 | m3 | Celá stěna | Stávající | Zednické práce | ZDIVO Z CDm | yes | 1652Stě0798445015 | m3 | Stěna | 0 | 0.5 | 9.923 | 2.891 | 4.961 | 3.15 | 1.956 | 1.575 | 3.15
ZDIVO Z CDm | Půdorys 3.NP | EPS 0.1 m, ZDIVO Z CDm 0.5 m | 1 | ZDIVO Z CDm | A | 1652HWa0000000025 | m3 | Celá stěna | Stávající | Zateplovací systémy | EPS | no | 1652Stě0000000026 | m2 | Stěna | 0 | 0.6 | 3.145 | 3.145 | 0.984 | 0.675 | 0.984 | 0.305 | 3.4 | NEMSOK - Object Layer Attributes #2, 2D interakce: yes; Object Layer Attributes #2, Status: Stávající; Object Layer Attributes #2, Práce: Zednické práce; Object Layer Attributes #2, Materiál: ZDIVO Z CDm; Object Layer Attributes #2, Allright_Stavebni_dil_ID: 1652Stě0798445109; Object Layer Attributes #2, Jednotka: m3; Object Layer Attributes #2, Název_objektu: Stěna; Object Layer Attributes #2, Staticky nosná konstrukce: yes
ZDIVO Z CDm | Půdorys 3.NP | EPS 0.1 m, ZDIVO Z CDm 0.5 m | 1 | ZDIVO Z CDm | A | 1652HWa0798445051 | m3 | Celá stěna | Stávající | Zateplovací systémy | EPS | no | 1652Stě0798445074 | m2 | Stěna | 0 | 0.6 | 18.275 | 18.275 | 10.136 | 5.325 | 10.136 | 3.175 | 3.4 | NEMSOK - Object Layer Attributes #2, 2D interakce: yes; Object Layer Attributes #2, Status: Stávající; Object Layer Attributes #2, Práce: Zednické práce; Object Layer Attributes #2, Materiál: ZDIVO Z CDm; Object Layer Attributes #2, Allright_Stavebni_dil_ID: 1652Stě0798445154; Object Layer Attributes #2, Jednotka: m3; Object Layer Attributes #2, Název_objektu: Stěna; Object Layer Attributes #2, Staticky nosná konstrukce: yes
ZDIVO Z CDm | Půdorys 3.NP | ZDIVO Z CDm 0.3 m | 1 | ZDIVO Z CDm | A | 1652HWa0798442354 | m3 | Celá stěna | Stávající | Zednické práce | ZDIVO Z CDm |  | 1652Stě0798442361 | m3 | Stěna | 0 | 0.3 | 7.507 | 1.838 | 2.252 | 2.275 | 0.415 | 0.682 | 3.3
ZDIVO Z CDm | Půdorys 3.NP | ZDIVO Z CDm 0.125 m | 1 | ZDIVO Z CDm | A | 1652HWa0798445956 | m3 | Celá stěna | Stávající | Zednické práce | ZDIVO Z CDm |  | 1652Stě0798445957 | m3 | Stěna | 0 | 0.125 | 0.61 | 0.61 | 0.076 | 0.2 | 0.076 | 0.025 | 3.05
ZDIVO Z CDm | Půdorys 3.NP | ZDIVO 0.15 m |  | ZDIVO Z CDm | A | 1652HWa0798432278 | m3 | Celá stěna | Stávající | Zednické práce | ZDIVO |  | 1652Stě0798432286 | m3 | Stěna | 0 | 0.15 | 0.9 | 0.9 | 0.135 | 0.9 | 0.135 | 0.135 | 1
ZELEZOBETONOVÁ KCE | Půdorys 3.NP | ZELEZOBETONOVÁ KCE 0.3 m |  | ZELEZOBETONOVÁ KCE | A | 1652HWa0798424479 | m3 | Celá stěna | Stávající | Betonářské práce | ZELEZOBETONOVÁ KCE |  | 1652Stě0798424480 | m3 | Stěna | 0 | 0.3 | 0.85 | 0.85 | 0.255 | 1 | 0.252 | 0.3 | 0.85
ZELEZOBETONOVÁ KCE | Půdorys 3.NP | ZELEZOBETONOVÁ KCE 0.2 m |  | ZELEZOBETONOVÁ KCE | A | 1652HWa0798424234 | m3 | Celá stěna | Stávající | Betonářské práce | ZELEZOBETONOVÁ KCE |  | 1652Stě0798424235 | m3 | Stěna | 0 | 0.2 | 12.24 | 12.24 | 2.448 | 14.4 | 2.442 | 2.88 | 0.85
ZELEZOBETONOVÁ KCE | Půdorys 3.NP | ZELEZOBETONOVÁ KCE 0.3 m |  | ZELEZOBETONOVÁ KCE | A | 1652HWa0798424460 | m3 | Celá stěna | Stávající | Betonářské práce | ZELEZOBETONOVÁ KCE |  | 1652Stě0798424461 | m3 | Stěna | 0 | 0.3 | 0.85 | 0.85 | 0.255 | 1 | 0.255 | 0.3 | 0.85
ZELEZOBETONOVÁ KCE | Půdorys 3.NP | ZELEZOBETONOVÁ KCE 0.32 m |  | ZELEZOBETONOVÁ KCE | A | 1652HWa0798424194 | m3 | Celá stěna | Stávající | Betonářské práce | ZELEZOBETONOVÁ KCE |  | 1652Stě0798424195 | m3 | Stěna | 0 | 0.32 | 20.825 | 20.375 | 6.664 | 24.5 | 6.52 | 7.84 | 0.85
ZELEZOBETONOVÁ KCE | Půdorys 3.NP | ZELEZOBETONOVÁ KCE 0.32 m |  | ZELEZOBETONOVÁ KCE | A | 1652HWa0798424270 | m3 | Celá stěna | Stávající | Betonářské práce | ZELEZOBETONOVÁ KCE |  | 1652Stě0798424271 | m3 | Stěna | 0 | 0.32 | 20.825 | 20.375 | 6.664 | 24.5 | 6.52 | 7.84 | 0.85
ZDIVO Z CDm | Půdorys 3.NP | ZDIVO 0.15 m |  | ZDIVO Z CDm | A | 1652HWa0798432137 | m3 | Celá stěna | Stávající | Zednické práce | ZDIVO |  | 1652Stě0798432135 | m3 | Stěna | 0 | 0.15 | 0.84 | 0.84 | 0.126 | 1.05 | 0.126 | 0.158 | 0.8
ZDIVO Z CDm | Půdorys 3.NP | EPS 0.1 m, ZDIVO Z CDm 0.5 m |  | ZDIVO Z CDm | A | 1652HWa0000000015 | m3 | Celá stěna | Stávající | Zateplovací systémy | EPS | no | 1652Stě0000000016 | m2 | Stěna | 0 | 0.6 | 29.925 | 26.445 | 16.936 | 10 | 14.848 | 5.8 | 3.15 | NEMSOK - Object Layer Attributes #2, 2D interakce: yes; Object Layer Attributes #2, Status: Stávající; Object Layer Attributes #2, Práce: Zednické práce; Object Layer Attributes #2, Materiál: ZDIVO Z CDm; Object Layer Attributes #2, Allright_Stavebni_dil_ID: 1652Stě0798445190; Object Layer Attributes #2, Jednotka: m3; Object Layer Attributes #2, Název_objektu: Stěna; Object Layer Attributes #2, Staticky nosná konstrukce: yes
EPS | Půdorys 3.NP | EPS 0.1 m |  | EPS |  | 1654HWa0000000576 | m3 | Celá stěna | Stávající | Zateplovací systémy | EPS | no | 1654Stě0000000591 | m2 | Stěna |  | 0.1 | 0.55 | 0.55 | 0.055 | 2.2 | 0.055 | 0.22 | 0.25
EPS | Půdorys 3.NP | EPS 0.1 m |  | EPS |  | 1654HWa0000000578 | m3 | Celá stěna | Stávající | Zateplovací systémy | EPS | no | 1654Stě0000000589 | m2 | Stěna |  | 0.1 | 1.15 | 1.15 | 0.115 | 4.6 | 0.115 | 0.46 | 0.25
EPS | Půdorys 3.NP | EPS 0.1 m |  | EPS |  | 1654HWa0000000579 | m3 | Celá stěna | Stávající | Zateplovací systémy | EPS | no | 1654Stě0000000585 | m2 | Stěna |  | 0.1 | 1.15 | 1.15 | 0.115 | 4.6 | 0.115 | 0.46 | 0.25
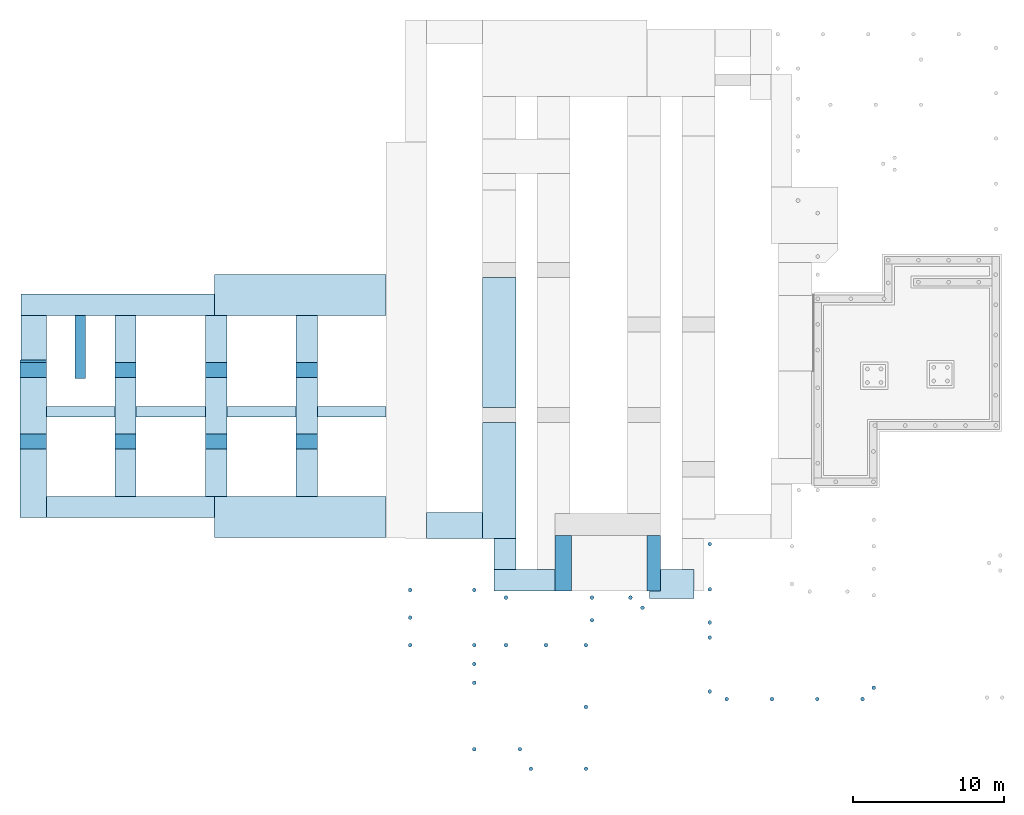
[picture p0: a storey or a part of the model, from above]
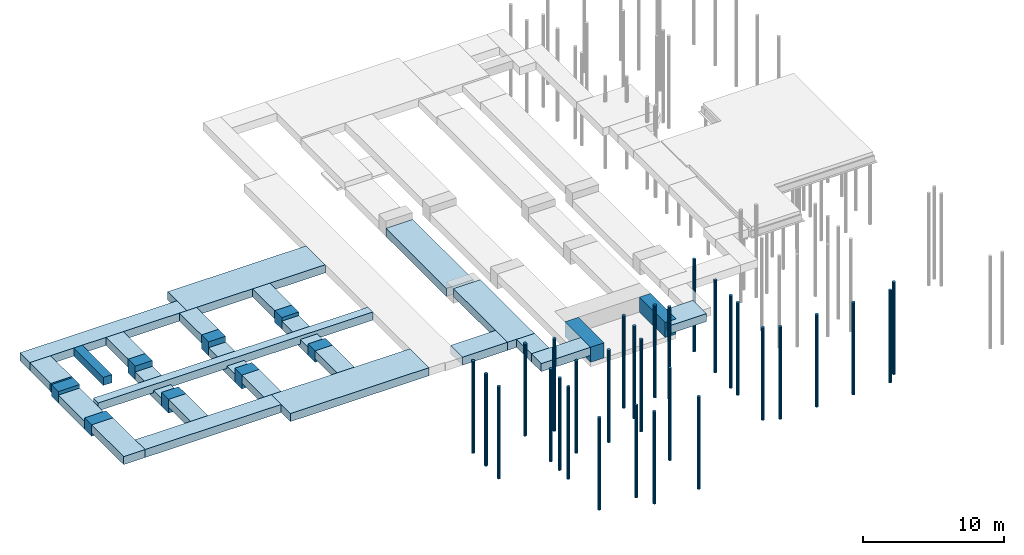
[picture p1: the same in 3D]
Properties of the parts of a building model (IFC4), part 40 of 45

# IfcWall (2385)
Name | In | Material | Faktor | Označení | Požární odolnost | Allright_Stavebni_dil_ID | Jednotka | Název_objektu | Object Layer Attributes #1, Status | Object Layer Attributes #1, Práce | Object Layer Attributes #1, Materiál | Object Layer Attributes #1, Staticky nosná konstrukce | Object Layer Attributes #1, Allright_Stavebni_dil_ID | Object Layer Attributes #1, Jednotka | Object Layer Attributes #1, Název_objektu | ThermalTransmittance (W/K/m2) | Width (m) | GrossSideArea (m2) | NetSideArea (m2) | GrossVolume (m3) | Length (m) | NetVolume (m3) | GrossFootprintArea (m2) | Height (m)
 | Půdorys 3.NP | ZELEZOBETONOVÁ KCE 0.5 m |  |  |  | 1654HWa0000000231 | m3 | Celá stěna | Stávající | Betonářské práce | ZELEZOBETONOVÁ KCE | yes | 1654Ven0000000232 | m2 | Věnec |  | 0.5 | 0.75 | 0.75 | 0.375 | 0 | 0.375 | 1.5 | 0.25
 | Půdorys 3.NP | ZELEZOBETONOVÁ KCE 0.5 m |  |  |  | 1654HWa0000000226 | m3 | Celá stěna | Stávající | Betonářské práce | ZELEZOBETONOVÁ KCE | yes | 1654Ven0000000227 | m2 | Věnec |  | 0.5 | 1.888 | 1.888 | 0.944 | 0 | 0.944 | 3.775 | 0.25
 | Půdorys 3.NP | ZELEZOBETONOVÁ KCE 0.5 m |  |  |  | 1654HWa0000000241 | m3 | Celá stěna | Stávající | Betonářské práce | ZELEZOBETONOVÁ KCE | yes | 1654Ven0000000242 | m2 | Věnec |  | 0.5 | 1.888 | 1.888 | 0.944 | 0 | 0.944 | 3.775 | 0.25
 | Půdorys 3.NP | ZELEZOBETONOVÁ KCE 0.45 m, LIGNOPOR 0.05 m |  |  |  | 1654HWa0000000060 | m3 | Celá stěna | Stávající | Betonářské práce | ZELEZOBETONOVÁ KCE | yes | 1654Ven0000000061 | m2 | Věnec |  | 0.5 | 2.625 | 2.625 | 1.301 | 0 | 1.301 | 5.205 | 0.25 | NEMSOK - Object Layer Attributes #2, 2D interakce: yes; Object Layer Attributes #2, Status: Stávající; Object Layer Attributes #2, Práce: Zateplovací systémy; Object Layer Attributes #2, Materiál: LIGNOPOR; Object Layer Attributes #2, Allright_Stavebni_dil_ID: 1654Ven0000000062; Object Layer Attributes #2, Jednotka: m2; Object Layer Attributes #2, Název_objektu: Věnec; Object Layer Attributes #2, Staticky nosná konstrukce: no
 | Půdorys 3.NP | ZELEZOBETONOVÁ KCE 0.45 m, LIGNOPOR 0.05 m |  |  |  | 1654HWa0000000068 | m3 | Celá stěna | Stávající | Betonářské práce | ZELEZOBETONOVÁ KCE | yes | 1654Ven0000000069 | m2 | Věnec |  | 0.5 | 2.325 | 2.325 | 1.106 | 0 | 1.106 | 4.425 | 0.25 | NEMSOK - Object Layer Attributes #2, 2D interakce: yes; Object Layer Attributes #2, Status: Stávající; Object Layer Attributes #2, Práce: Zateplovací systémy; Object Layer Attributes #2, Materiál: LIGNOPOR; Object Layer Attributes #2, Allright_Stavebni_dil_ID: 1654Ven0000000070; Object Layer Attributes #2, Jednotka: m2; Object Layer Attributes #2, Název_objektu: Věnec; Object Layer Attributes #2, Staticky nosná konstrukce: no
 | Půdorys 3.NP | ZELEZOBETONOVÁ KCE 0.45 m, LIGNOPOR 0.05 m |  |  |  | 1654HWa0000000085 | m3 | Celá stěna | Stávající | Betonářské práce | ZELEZOBETONOVÁ KCE | yes | 1654Ven0000000086 | m2 | Věnec |  | 0.5 | 0.837 | 0.838 | 0.362 | 0 | 0.362 | 1.45 | 0.25 | NEMSOK - Object Layer Attributes #2, 2D interakce: yes; Object Layer Attributes #2, Status: Stávající; Object Layer Attributes #2, Práce: Zateplovací systémy; Object Layer Attributes #2, Materiál: LIGNOPOR; Object Layer Attributes #2, Allright_Stavebni_dil_ID: 1654Ven0000000087; Object Layer Attributes #2, Jednotka: m2; Object Layer Attributes #2, Název_objektu: Věnec; Object Layer Attributes #2, Staticky nosná konstrukce: no
 | Půdorys 3.NP | ZELEZOBETONOVÁ KCE 0.45 m, LIGNOPOR 0.05 m |  |  |  | 1654HWa0000000106 | m3 | Celá stěna | Stávající | Betonářské práce | ZELEZOBETONOVÁ KCE | yes | 1654Ven0000000107 | m2 | Věnec |  | 0.5 | 0.188 | 0.188 | 0.049 | 0 | 0.049 | 0.195 | 0.25 | NEMSOK - Object Layer Attributes #2, 2D interakce: yes; Object Layer Attributes #2, Status: Stávající; Object Layer Attributes #2, Práce: Zateplovací systémy; Object Layer Attributes #2, Materiál: LIGNOPOR; Object Layer Attributes #2, Allright_Stavebni_dil_ID: 1654Ven0000000108; Object Layer Attributes #2, Jednotka: m2; Object Layer Attributes #2, Název_objektu: Věnec; Object Layer Attributes #2, Staticky nosná konstrukce: no
 | Půdorys 3.NP | ZELEZOBETONOVÁ KCE 0.45 m, LIGNOPOR 0.05 m |  |  |  | 1654HWa0000000127 | m3 | Celá stěna | Stávající | Betonářské práce | ZELEZOBETONOVÁ KCE | yes | 1654Ven0000000128 | m2 | Věnec |  | 0.5 | 1.775 | 1.775 | 0.887 | 0 | 0.887 | 3.55 | 0.25 | NEMSOK - Object Layer Attributes #2, 2D interakce: yes; Object Layer Attributes #2, Status: Stávající; Object Layer Attributes #2, Práce: Zateplovací systémy; Object Layer Attributes #2, Materiál: LIGNOPOR; Object Layer Attributes #2, Allright_Stavebni_dil_ID: 1654Ven0000000129; Object Layer Attributes #2, Jednotka: m2; Object Layer Attributes #2, Název_objektu: Věnec; Object Layer Attributes #2, Staticky nosná konstrukce: no
 | Půdorys 3.NP | ZELEZOBETONOVÁ KCE 0.45 m, LIGNOPOR 0.05 m |  |  |  | 1654HWa0000000038 | m3 | Celá stěna | Stávající | Betonářské práce | ZELEZOBETONOVÁ KCE | yes | 1654Ven0000000039 | m2 | Věnec |  | 0.5 | 2.125 | 2.125 | 1.006 | 0 | 1.006 | 4.025 | 0.25 | NEMSOK - Object Layer Attributes #2, 2D interakce: yes; Object Layer Attributes #2, Status: Stávající; Object Layer Attributes #2, Práce: Zateplovací systémy; Object Layer Attributes #2, Materiál: LIGNOPOR; Object Layer Attributes #2, Allright_Stavebni_dil_ID: 1654Ven0000000040; Object Layer Attributes #2, Jednotka: m2; Object Layer Attributes #2, Název_objektu: Věnec; Object Layer Attributes #2, Staticky nosná konstrukce: no
MINERÁLNÍ VATA | Půdorys 3.NP | MINERÁLNÍ VATA 0.15 m |  | MINERÁLNÍ VATA |  | 1664HWa0000000547 | m3 | Celá stěna | Nový | Zateplovací systémy | MINERÁLNÍ VATA | no | 1664Stě0000000548 | m3 | Stěna |  | 0.15 | 1.008 | 1.008 | 0.151 | 1.2 | 0.151 | 0.18 | 0.84 | NEMSOK - Object Layer Attributes #1, Kód prvku: TI06.05.1001; Object Layer Attributes #1, Požární odolnost: A1; Object Layer Attributes #1, Systém kotvení: -; Object Layer Attributes #1, Součinitel prostupu tepla: 0.036; Object Layer Attributes #1, Součinitel difúzního odporu: 1; Object Layer Attributes #1, Způsob spojení vrstev: Lepený + mechanicky kotvený
MINERÁLNÍ VATA | Půdorys 3.NP | MINERÁLNÍ VATA 0.15 m |  | MINERÁLNÍ VATA |  | 1664HWa0000000552 | m3 | Celá stěna | Nový | Zateplovací systémy | MINERÁLNÍ VATA | no | 1664Stě0000000553 | m3 | Stěna |  | 0.15 | 1.008 | 1.008 | 0.151 | 1.2 | 0.151 | 0.18 | 0.84 | NEMSOK - Object Layer Attributes #1, Kód prvku: TI06.05.1002; Object Layer Attributes #1, Požární odolnost: A1; Object Layer Attributes #1, Systém kotvení: -; Object Layer Attributes #1, Součinitel prostupu tepla: 0.036; Object Layer Attributes #1, Součinitel difúzního odporu: 1; Object Layer Attributes #1, Způsob spojení vrstev: Lepený + mechanicky kotvený
MINERÁLNÍ VATA | Půdorys 3.NP | MINERÁLNÍ VATA 0.15 m |  | MINERÁLNÍ VATA |  | 1664HWa0000000562 | m3 | Celá stěna | Nový | Zateplovací systémy | MINERÁLNÍ VATA | no | 1664Stě0000000563 | m3 | Stěna |  | 0.15 | 0.882 | 0.882 | 0.132 | 1.05 | 0.132 | 0.158 | 0.84 | NEMSOK - Object Layer Attributes #1, Kód prvku: TI06.05.1003; Object Layer Attributes #1, Požární odolnost: A1; Object Layer Attributes #1, Systém kotvení: -; Object Layer Attributes #1, Součinitel prostupu tepla: 0.036; Object Layer Attributes #1, Součinitel difúzního odporu: 1; Object Layer Attributes #1, Způsob spojení vrstev: Lepený + mechanicky kotvený
MINERÁLNÍ VATA | Půdorys 3.NP | MINERÁLNÍ VATA 0.15 m |  | MINERÁLNÍ VATA |  | 1664HWa0000000611 | m3 | Celá stěna | Nový | Zateplovací systémy | MINERÁLNÍ VATA | no | 1664Stě0000000612 | m3 | Stěna |  | 0.15 | 16.905 | 16.905 | 2.536 | 24.5 | 2.536 | 3.675 | 0.69 | NEMSOK - Object Layer Attributes #1, Kód prvku: TI06.05.1004; Object Layer Attributes #1, Požární odolnost: A1; Object Layer Attributes #1, Systém kotvení: -; Object Layer Attributes #1, Součinitel prostupu tepla: 0.036; Object Layer Attributes #1, Součinitel difúzního odporu: 1; Object Layer Attributes #1, Způsob spojení vrstev: Lepený + mechanicky kotvený
MINERÁLNÍ VATA | Půdorys 3.NP | MINERÁLNÍ VATA 0.22 m |  | MINERÁLNÍ VATA |  | 1664HWa0000000637 | m3 | Celá stěna | Nový | Zateplovací systémy | MINERÁLNÍ VATA | no | 1664Stě0000000638 | m3 | Stěna |  | 0.22 | 0.552 | 0.552 | 0.121 | 0.8 | 0.121 | 0.176 | 0.69 | NEMSOK - Object Layer Attributes #1, Kód prvku: TI06.05.1005; Object Layer Attributes #1, Požární odolnost: A1; Object Layer Attributes #1, Systém kotvení: -; Object Layer Attributes #1, Součinitel prostupu tepla: 0.036; Object Layer Attributes #1, Součinitel difúzního odporu: 1; Object Layer Attributes #1, Způsob spojení vrstev: Lepený + mechanicky kotvený
MINERÁLNÍ VATA | Půdorys 3.NP | MINERÁLNÍ VATA 0.22 m |  | MINERÁLNÍ VATA |  | 1664HWa0000000645 | m3 | Celá stěna | Nový | Zateplovací systémy | MINERÁLNÍ VATA | no | 1664Stě0000000646 | m3 | Stěna |  | 0.22 | 0.552 | 0.552 | 0.121 | 0.8 | 0.121 | 0.176 | 0.69 | NEMSOK - Object Layer Attributes #1, Kód prvku: TI06.05.1006; Object Layer Attributes #1, Požární odolnost: A1; Object Layer Attributes #1, Systém kotvení: -; Object Layer Attributes #1, Součinitel prostupu tepla: 0.036; Object Layer Attributes #1, Součinitel difúzního odporu: 1; Object Layer Attributes #1, Způsob spojení vrstev: Lepený + mechanicky kotvený
MINERÁLNÍ VATA | Půdorys 3.NP | MINERÁLNÍ VATA 0.15 m |  | MINERÁLNÍ VATA |  | 1664HWa0000000650 | m3 | Celá stěna | Nový | Zateplovací systémy | MINERÁLNÍ VATA | no | 1664Stě0000000651 | m3 | Stěna |  | 0.15 | 9.632 | 9.632 | 1.445 | 13.96 | 1.445 | 2.094 | 0.69 | NEMSOK - Object Layer Attributes #1, Kód prvku: TI06.05.1007; Object Layer Attributes #1, Požární odolnost: A1; Object Layer Attributes #1, Systém kotvení: -; Object Layer Attributes #1, Součinitel prostupu tepla: 0.036; Object Layer Attributes #1, Součinitel difúzního odporu: 1; Object Layer Attributes #1, Způsob spojení vrstev: Lepený + mechanicky kotvený
MINERÁLNÍ VATA | Půdorys 3.NP | MINERÁLNÍ VATA 0.15 m |  | MINERÁLNÍ VATA |  | 1664HWa0000000666 | m3 | Celá stěna | Nový | Zateplovací systémy | MINERÁLNÍ VATA | no | 1664Stě0000000667 | m3 | Stěna |  | 0.15 | 10.733 | 10.733 | 1.61 | 15.555 | 1.61 | 2.333 | 0.69 | NEMSOK - Object Layer Attributes #1, Kód prvku: TI06.05.1008; Object Layer Attributes #1, Požární odolnost: A1; Object Layer Attributes #1, Systém kotvení: -; Object Layer Attributes #1, Součinitel prostupu tepla: 0.036; Object Layer Attributes #1, Součinitel difúzního odporu: 1; Object Layer Attributes #1, Způsob spojení vrstev: Lepený + mechanicky kotvený
MINERÁLNÍ VATA | Půdorys 3.NP | MINERÁLNÍ VATA 0.22 m |  | MINERÁLNÍ VATA |  | 1664HWa0000000671 | m3 | Celá stěna | Nový | Zateplovací systémy | MINERÁLNÍ VATA | no | 1664Stě0000000672 | m3 | Stěna |  | 0.22 | 9.632 | 9.632 | 2.119 | 13.96 | 2.119 | 3.071 | 0.69 | NEMSOK - Object Layer Attributes #1, Kód prvku: TI06.05.1009; Object Layer Attributes #1, Požární odolnost: A1; Object Layer Attributes #1, Systém kotvení: -; Object Layer Attributes #1, Součinitel prostupu tepla: 0.036; Object Layer Attributes #1, Součinitel difúzního odporu: 1; Object Layer Attributes #1, Způsob spojení vrstev: Lepený + mechanicky kotvený
MINERÁLNÍ VATA | Půdorys 3.NP | MINERÁLNÍ VATA 0.15 m |  | MINERÁLNÍ VATA |  | 1664HWa0000000686 | m3 | Celá stěna | Nový | Zateplovací systémy | MINERÁLNÍ VATA | no | 1664Stě0000000687 | m3 | Stěna |  | 0.15 | 0.756 | 0.756 | 0.113 | 0.9 | 0.113 | 0.135 | 0.84 | NEMSOK - Object Layer Attributes #1, Kód prvku: TI06.05.1010; Object Layer Attributes #1, Požární odolnost: A1; Object Layer Attributes #1, Systém kotvení: -; Object Layer Attributes #1, Součinitel prostupu tepla: 0.036; Object Layer Attributes #1, Součinitel difúzního odporu: 1; Object Layer Attributes #1, Způsob spojení vrstev: Lepený + mechanicky kotvený
MINERÁLNÍ VATA | Půdorys 3.NP | MINERÁLNÍ VATA 0.15 m |  | MINERÁLNÍ VATA |  | 1664HWa0000000691 | m3 | Celá stěna | Nový | Zateplovací systémy | MINERÁLNÍ VATA | no | 1664Stě0000000692 | m3 | Stěna |  | 0.15 | 0.63 | 0.63 | 0.095 | 0.75 | 0.095 | 0.113 | 0.84 | NEMSOK - Object Layer Attributes #1, Kód prvku: TI06.05.1011; Object Layer Attributes #1, Požární odolnost: A1; Object Layer Attributes #1, Systém kotvení: -; Object Layer Attributes #1, Součinitel prostupu tepla: 0.036; Object Layer Attributes #1, Součinitel difúzního odporu: 1; Object Layer Attributes #1, Způsob spojení vrstev: Lepený + mechanicky kotvený
MINERÁLNÍ VATA | Půdorys 3.NP | MINERÁLNÍ VATA 0.15 m |  | MINERÁLNÍ VATA |  | 1664HWa0000000701 | m3 | Celá stěna | Nový | Zateplovací systémy | MINERÁLNÍ VATA | no | 1664Stě0000000702 | m3 | Stěna |  | 0.15 | 0.63 | 0.63 | 0.095 | 0.75 | 0.095 | 0.112 | 0.84 | NEMSOK - Object Layer Attributes #1, Kód prvku: TI06.05.1012; Object Layer Attributes #1, Požární odolnost: A1; Object Layer Attributes #1, Systém kotvení: -; Object Layer Attributes #1, Součinitel prostupu tepla: 0.036; Object Layer Attributes #1, Součinitel difúzního odporu: 1; Object Layer Attributes #1, Způsob spojení vrstev: Lepený + mechanicky kotvený
MINERÁLNÍ VATA | Půdorys 3.NP | MINERÁLNÍ VATA 0.15 m |  | MINERÁLNÍ VATA |  | 1664HWa0000000713 | m3 | Celá stěna | Nový | Zateplovací systémy | MINERÁLNÍ VATA | no | 1664Stě0000000714 | m3 | Stěna |  | 0.15 | 0.504 | 0.504 | 0.076 | 0.6 | 0.076 | 0.09 | 0.84 | NEMSOK - Object Layer Attributes #1, Kód prvku: TI06.05.1013; Object Layer Attributes #1, Požární odolnost: A1; Object Layer Attributes #1, Systém kotvení: -; Object Layer Attributes #1, Součinitel prostupu tepla: 0.036; Object Layer Attributes #1, Součinitel difúzního odporu: 1; Object Layer Attributes #1, Způsob spojení vrstev: Lepený + mechanicky kotvený
MINERÁLNÍ VATA | Půdorys 3.NP | MINERÁLNÍ VATA 0.15 m |  | MINERÁLNÍ VATA |  | 1664HWa0000000791 | m3 | Celá stěna | Nový | Zateplovací systémy | MINERÁLNÍ VATA | no | 1664Stě0000000792 | m3 | Stěna |  | 0.15 | 5.758 | 5.758 | 0.864 | 8.345 | 0.864 | 1.252 | 0.69 | NEMSOK - Object Layer Attributes #1, Kód prvku: TI06.05.1014; Object Layer Attributes #1, Požární odolnost: A1; Object Layer Attributes #1, Systém kotvení: -; Object Layer Attributes #1, Součinitel prostupu tepla: 0.036; Object Layer Attributes #1, Součinitel difúzního odporu: 1; Object Layer Attributes #1, Způsob spojení vrstev: Lepený + mechanicky kotvený
MINERÁLNÍ VATA | Půdorys 3.NP | MINERÁLNÍ VATA 0.15 m |  | MINERÁLNÍ VATA |  | 1664HWa0000000799 | m3 | Celá stěna | Nový | Zateplovací systémy | MINERÁLNÍ VATA | no | 1664Stě0000000800 | m3 | Stěna |  | 0.15 | 0.756 | 0.756 | 0.113 | 0.9 | 0.113 | 0.135 | 0.84 | NEMSOK - Object Layer Attributes #1, Kód prvku: TI06.05.1015; Object Layer Attributes #1, Požární odolnost: A1; Object Layer Attributes #1, Systém kotvení: -; Object Layer Attributes #1, Součinitel prostupu tepla: 0.036; Object Layer Attributes #1, Součinitel difúzního odporu: 1; Object Layer Attributes #1, Způsob spojení vrstev: Lepený + mechanicky kotvený
MINERÁLNÍ VATA | Půdorys 3.NP | MINERÁLNÍ VATA 0.15 m |  | MINERÁLNÍ VATA |  | 1664HWa0000000804 | m3 | Celá stěna | Nový | Zateplovací systémy | MINERÁLNÍ VATA | no | 1664Stě0000000805 | m3 | Stěna |  | 0.15 | 0.63 | 0.63 | 0.095 | 0.75 | 0.095 | 0.113 | 0.84 | NEMSOK - Object Layer Attributes #1, Kód prvku: TI06.05.1016; Object Layer Attributes #1, Požární odolnost: A1; Object Layer Attributes #1, Systém kotvení: -; Object Layer Attributes #1, Součinitel prostupu tepla: 0.036; Object Layer Attributes #1, Součinitel difúzního odporu: 1; Object Layer Attributes #1, Způsob spojení vrstev: Lepený + mechanicky kotvený
MINERÁLNÍ VATA | Půdorys 3.NP | MINERÁLNÍ VATA 0.15 m |  | MINERÁLNÍ VATA |  | 1664HWa0000000814 | m3 | Celá stěna | Nový | Zateplovací systémy | MINERÁLNÍ VATA | no | 1664Stě0000000815 | m3 | Stěna |  | 0.15 | 0.63 | 0.63 | 0.095 | 0.75 | 0.095 | 0.113 | 0.84 | NEMSOK - Object Layer Attributes #1, Kód prvku: TI06.05.1017; Object Layer Attributes #1, Požární odolnost: A1; Object Layer Attributes #1, Systém kotvení: -; Object Layer Attributes #1, Součinitel prostupu tepla: 0.036; Object Layer Attributes #1, Součinitel difúzního odporu: 1; Object Layer Attributes #1, Způsob spojení vrstev: Lepený + mechanicky kotvený
MINERÁLNÍ VATA | Půdorys 3.NP | MINERÁLNÍ VATA 0.15 m |  | MINERÁLNÍ VATA |  | 1664HWa0000000826 | m3 | Celá stěna | Nový | Zateplovací systémy | MINERÁLNÍ VATA | no | 1664Stě0000000827 | m3 | Stěna |  | 0.15 | 0.504 | 0.504 | 0.076 | 0.6 | 0.076 | 0.09 | 0.84 | NEMSOK - Object Layer Attributes #1, Kód prvku: TI06.05.1018; Object Layer Attributes #1, Požární odolnost: A1; Object Layer Attributes #1, Systém kotvení: -; Object Layer Attributes #1, Součinitel prostupu tepla: 0.036; Object Layer Attributes #1, Součinitel difúzního odporu: 1; Object Layer Attributes #1, Způsob spojení vrstev: Lepený + mechanicky kotvený
MINERÁLNÍ VATA | Půdorys 3.NP | MINERÁLNÍ VATA 0.15 m |  | MINERÁLNÍ VATA |  | 1664HWa0000000861 | m3 | Celá stěna | Nový | Zateplovací systémy | MINERÁLNÍ VATA | no | 1664Stě0000000862 | m3 | Stěna |  | 0.15 | 0.768 | 0.768 | 0.115 | 1.2 | 0.115 | 0.18 | 0.64 | NEMSOK - Object Layer Attributes #1, Kód prvku: TI06.05.1019; Object Layer Attributes #1, Požární odolnost: A1; Object Layer Attributes #1, Systém kotvení: -; Object Layer Attributes #1, Součinitel prostupu tepla: 0.036; Object Layer Attributes #1, Součinitel difúzního odporu: 1; Object Layer Attributes #1, Způsob spojení vrstev: Lepený + mechanicky kotvený
MINERÁLNÍ VATA | Půdorys 3.NP | MINERÁLNÍ VATA 0.15 m |  | MINERÁLNÍ VATA |  | 1664HWa0000000871 | m3 | Celá stěna | Nový | Zateplovací systémy | MINERÁLNÍ VATA | no | 1664Stě0000000872 | m3 | Stěna |  | 0.15 | 0.48 | 0.48 | 0.072 | 0.75 | 0.072 | 0.112 | 0.64 | NEMSOK - Object Layer Attributes #1, Kód prvku: TI06.05.1020; Object Layer Attributes #1, Požární odolnost: A1; Object Layer Attributes #1, Systém kotvení: -; Object Layer Attributes #1, Součinitel prostupu tepla: 0.036; Object Layer Attributes #1, Součinitel difúzního odporu: 1; Object Layer Attributes #1, Způsob spojení vrstev: Lepený + mechanicky kotvený
MINERÁLNÍ VATA | Půdorys 3.NP | MINERÁLNÍ VATA 0.15 m |  | MINERÁLNÍ VATA |  | 1664HWa0000000881 | m3 | Celá stěna | Nový | Zateplovací systémy | MINERÁLNÍ VATA | no | 1664Stě0000000882 | m3 | Stěna |  | 0.15 | 0.672 | 0.672 | 0.101 | 1.05 | 0.101 | 0.158 | 0.64 | NEMSOK - Object Layer Attributes #1, Kód prvku: TI06.05.1021; Object Layer Attributes #1, Požární odolnost: A1; Object Layer Attributes #1, Systém kotvení: -; Object Layer Attributes #1, Součinitel prostupu tepla: 0.036; Object Layer Attributes #1, Součinitel difúzního odporu: 1; Object Layer Attributes #1, Způsob spojení vrstev: Lepený + mechanicky kotvený
MINERÁLNÍ VATA | Půdorys 3.NP | MINERÁLNÍ VATA 0.05 m |  | MINERÁLNÍ VATA |  | 1664HWa0000000907 | m3 | Celá stěna | Nový | Zateplovací systémy | MINERÁLNÍ VATA | no | 1664Stě0000000908 | m3 | Stěna |  | 0.05 | 0.384 | 0.384 | 0.019 | 0.6 | 0.019 | 0.03 | 0.64 | NEMSOK - Object Layer Attributes #1, Kód prvku: TI06.05.1022; Object Layer Attributes #1, Požární odolnost: A1; Object Layer Attributes #1, Systém kotvení: -; Object Layer Attributes #1, Součinitel prostupu tepla: 0.036; Object Layer Attributes #1, Součinitel difúzního odporu: 1; Object Layer Attributes #1, Způsob spojení vrstev: Lepený + mechanicky kotvený
MINERÁLNÍ VATA | Půdorys 3.NP | MINERÁLNÍ VATA 0.15 m |  | MINERÁLNÍ VATA |  | 1664HWa0000000913 | m3 | Celá stěna | Nový | Zateplovací systémy | MINERÁLNÍ VATA | no | 1664Stě0000000914 | m3 | Stěna |  | 0.15 | 0.512 | 0.512 | 0.077 | 0.8 | 0.077 | 0.12 | 0.64 | NEMSOK - Object Layer Attributes #1, Kód prvku: TI06.05.1023; Object Layer Attributes #1, Požární odolnost: A1; Object Layer Attributes #1, Systém kotvení: -; Object Layer Attributes #1, Součinitel prostupu tepla: 0.036; Object Layer Attributes #1, Součinitel difúzního odporu: 1; Object Layer Attributes #1, Způsob spojení vrstev: Lepený + mechanicky kotvený
MINERÁLNÍ VATA | Půdorys 3.NP | MINERÁLNÍ VATA 0.15 m |  | MINERÁLNÍ VATA |  | 1664HWa0000000922 | m3 | Celá stěna | Nový | Zateplovací systémy | MINERÁLNÍ VATA | no | 1664Stě0000000923 | m3 | Stěna |  | 0.15 | 0.48 | 0.48 | 0.072 | 0.75 | 0.072 | 0.113 | 0.64 | NEMSOK - Object Layer Attributes #1, Kód prvku: TI06.05.1024; Object Layer Attributes #1, Požární odolnost: A1; Object Layer Attributes #1, Systém kotvení: -; Object Layer Attributes #1, Součinitel prostupu tepla: 0.036; Object Layer Attributes #1, Součinitel difúzního odporu: 1; Object Layer Attributes #1, Způsob spojení vrstev: Lepený + mechanicky kotvený
MINERÁLNÍ VATA | Půdorys 3.NP | MINERÁLNÍ VATA 0.15 m |  | MINERÁLNÍ VATA |  | 1664HWa0000000934 | m3 | Celá stěna | Nový | Zateplovací systémy | MINERÁLNÍ VATA | no | 1664Stě0000000935 | m3 | Stěna |  | 0.15 | 0.416 | 0.416 | 0.062 | 0.65 | 0.062 | 0.098 | 0.64 | NEMSOK - Object Layer Attributes #1, Kód prvku: TI06.05.1025; Object Layer Attributes #1, Požární odolnost: A1; Object Layer Attributes #1, Systém kotvení: -; Object Layer Attributes #1, Součinitel prostupu tepla: 0.036; Object Layer Attributes #1, Součinitel difúzního odporu: 1; Object Layer Attributes #1, Způsob spojení vrstev: Lepený + mechanicky kotvený
MINERÁLNÍ VATA | Půdorys 3.NP | MINERÁLNÍ VATA 0.15 m |  | MINERÁLNÍ VATA |  | 1664HWa0000004592 | m3 | Celá stěna | Nový | Zateplovací systémy | MINERÁLNÍ VATA | no | 1664Stě0000004595 | m3 | Stěna |  | 0.15 | 0.882 | 0.882 | 0.132 | 1.05 | 0.132 | 0.158 | 0.84 | NEMSOK - Object Layer Attributes #1, Kód prvku: TI06.05.1026; Object Layer Attributes #1, Požární odolnost: A1; Object Layer Attributes #1, Systém kotvení: -; Object Layer Attributes #1, Součinitel prostupu tepla: 0.036; Object Layer Attributes #1, Součinitel difúzního odporu: 1; Object Layer Attributes #1, Způsob spojení vrstev: Lepený + mechanicky kotvený
ZDIVO Z CDm | Půdorys 4.NP | ZDIVO Z CDm 0.5 m |  | ZDIVO Z CDm | A | 1752HWa0000000009 | m3 | Celá stěna | Stávající | Zednické práce | ZDIVO Z CDm | yes | 1752Stě0000000024 | m3 | Stěna | 0 | 0.5 | 16.077 | 16.078 | 8.039 | 5.45 | 8.039 | 2.725 | 2.95
ZDIVO Z CDm | Půdorys 4.NP | ZDIVO Z CDm 0.5 m |  | ZDIVO Z CDm | A | 1752HWa0000000011 | m3 | Celá stěna | Stávající | Zednické práce | ZDIVO Z CDm | yes | 1752Stě0000000048 | m3 | Stěna | 0 | 0.5 | 8.995 | 8.995 | 4.497 | 3.5 | 4.497 | 1.75 | 2.57
ZELEZOBETONOVÁ KCE | Půdorys 4.NP | ZELEZOBETONOVÁ KCE 0.3 m | 1 | ZELEZOBETONOVÁ KCE | A | 1752HWa0000007967 | m3 | Celá stěna | Stávající | Betonářské práce | ZELEZOBETONOVÁ KCE |  | 1752Stě0000010337 | m3 | Stěna | 0 | 0.3 | 3.366 | 3.366 | 1.01 | 1.02 | 1.01 | 0.306 | 3.3
ZELEZOBETONOVÁ KCE | Půdorys 4.NP | ZELEZOBETONOVÁ KCE 0.3 m | 1 | ZELEZOBETONOVÁ KCE | A | 1752HWa0000007974 | m3 | Celá stěna | Stávající | Betonářské práce | ZELEZOBETONOVÁ KCE |  | 1752Stě0000010082 | m3 | Stěna | 0 | 0.3 | 18.81 | 18.81 | 5.643 | 5.7 | 5.643 | 1.71 | 3.3
ZELEZOBETONOVÁ KCE | Půdorys 4.NP | ZELEZOBETONOVÁ KCE 0.32 m | 1 | ZELEZOBETONOVÁ KCE | A | 1752HWa0000007978 | m3 | Celá stěna | Stávající | Betonářské práce | ZELEZOBETONOVÁ KCE |  | 1752Stě0000010356 | m3 | Stěna | 0 | 0.32 | 27.72 | 19.395 | 8.87 | 8.4 | 6.078 | 2.688 | 3.3
ZELEZOBETONOVÁ KCE | Půdorys 4.NP | ZELEZOBETONOVÁ KCE 0.2 m | 1 | ZELEZOBETONOVÁ KCE | A | 1752HWa0000009496 | m3 | Celá stěna | Stávající | Betonářské práce | ZELEZOBETONOVÁ KCE | yes | 1752Stě0000010326 | m3 | Stěna | 0 | 0.2 | 10.065 | 10.065 | 2.013 | 3.3 | 2.013 | 0.66 | 3.05
ZELEZOBETONOVÁ KCE | Půdorys 4.NP | ZELEZOBETONOVÁ KCE 0.2 m | 1 | ZELEZOBETONOVÁ KCE | A | 1752HWa0000009513 | m3 | Celá stěna | Stávající | Betonářské práce | ZELEZOBETONOVÁ KCE | yes | 1752Stě0000009674 | m3 | Stěna | 0 | 0.2 | 16.47 | 16.47 | 3.294 | 5.4 | 3.294 | 1.08 | 3.05
ZELEZOBETONOVÁ KCE | Půdorys 4.NP | ZELEZOBETONOVÁ KCE 0.3 m | 1 | ZELEZOBETONOVÁ KCE | A | 1752HWa0000009528 | m3 | Celá stěna | Stávající | Betonářské práce | ZELEZOBETONOVÁ KCE |  | 1752Stě0000010112 | m3 | Stěna | 0 | 0.3 | 3.366 | 3.366 | 1.01 | 1.02 | 1.01 | 0.306 | 3.3
ZELEZOBETONOVÁ KCE | Půdorys 4.NP | ZELEZOBETONOVÁ KCE 0.3 m | 1 | ZELEZOBETONOVÁ KCE | A | 1752HWa0000009532 | m3 | Celá stěna | Stávající | Betonářské práce | ZELEZOBETONOVÁ KCE |  | 1752Stě0000009888 | m3 | Stěna | 0 | 0.3 | 3.366 | 3.366 | 1.01 | 1.02 | 1.01 | 0.306 | 3.3
ZELEZOBETONOVÁ KCE | Půdorys 4.NP | ZELEZOBETONOVÁ KCE 0.3 m | 1 | ZELEZOBETONOVÁ KCE | A | 1752HWa0000009882 | m3 | Celá stěna | Stávající | Betonářské práce | ZELEZOBETONOVÁ KCE |  | 1752Stě0000009886 | m3 | Stěna | 0 | 0.3 | 3.366 | 3.366 | 1.01 | 1.02 | 1.01 | 0.306 | 3.3
PLYNOSILIKÁT | Půdorys 4.NP | PLYNOSILIKÁT 0.32 m | 1 | PLYNOSILIKÁT | REI 180 | 1752HWa0000010327 | m3 | Celá stěna | Stávající | Zednické práce | PLYNOSILIKÁT |  | 1752Stě0000010448 | m3 | Stěna | 0.541 | 0.32 | 9.504 | 6.804 | 3.041 | 2.88 | 2.135 | 0.922 | 3.3 | Pset_WallCommon - AcousticRating: 48 dB
PLYNOSILIKÁT | Půdorys 4.NP | PLYNOSILIKÁT 0.32 m | 1 | PLYNOSILIKÁT | REI 180 | 1752HWa0000010343 | m3 | Celá stěna | Stávající | Zednické práce | PLYNOSILIKÁT |  | 1752Stě0000010458 | m3 | Stěna | 0.541 | 0.32 | 1.584 | 1.584 | 0.507 | 0.48 | 0.507 | 0.154 | 3.3 | Pset_WallCommon - AcousticRating: 48 dB
PLYNOSILIKÁT | Půdorys 4.NP | PLYNOSILIKÁT 0.32 m |  | PLYNOSILIKÁT | REI 180 | 1752HWa0000010359 | m3 | Celá stěna | Stávající | Zednické práce | PLYNOSILIKÁT |  | 1752Stě0000010443 | m3 | Stěna | 0.541 | 0.32 | 47.854 | 28.642 | 15.313 | 15.69 | 9.409 | 5.021 | 3.05 | Pset_WallCommon - AcousticRating: 48 dB
ZELEZOBETONOVÁ KCE | Půdorys 4.NP | ZELEZOBETONOVÁ KCE 0.2 m | 1 | ZELEZOBETONOVÁ KCE | A | 1752HWa0000012636 | m3 | Celá stěna | Stávající | Betonářské práce | ZELEZOBETONOVÁ KCE | yes | 1752Stě0000014170 | m3 | Stěna | 0 | 0.2 | 9.15 | 9.15 | 1.83 | 3 | 1.83 | 0.6 | 3.05
ZDIVO Z CDm | Půdorys 4.NP | ZDIVO Z CDm 0.25 m | 1 | ZDIVO Z CDm | A | 1752HWa0000012640 | m3 | Celá stěna | Stávající | Zednické práce | ZDIVO Z CDm | yes | 1752Stě0000014165 | m3 | Stěna | 0 | 0.25 | 15.25 | 8.244 | 3.812 | 5 | 2.061 | 1.25 | 3.05
ZDIVO Z CDm | Půdorys 4.NP | ZDIVO Z CDm 0.35 m | 1 | ZDIVO Z CDm | A | 1752HWa0000014158 | m3 | Celá stěna | Stávající | Zednické práce | ZDIVO Z CDm | yes | 1752Stě0000014172 | m3 | Stěna | 0 | 0.35 | 1.22 | 1.22 | 0.427 | 0.4 | 0.427 | 0.14 | 3.05
ZDIVO Z CDm | Půdorys 4.NP | ZDIVO Z CDm 0.35 m | 1 | ZDIVO Z CDm | A | 1752HWa0000014160 | m3 | Celá stěna | Stávající | Zednické práce | ZDIVO Z CDm | yes | 1752Stě0000014167 | m3 | Stěna | 0 | 0.35 | 1.22 | 1.22 | 0.427 | 0.4 | 0.427 | 0.14 | 3.05
PLYNOSILIKÁT | Půdorys 4.NP | PLYNOSILIKÁT 0.3 m | 1 | PLYNOSILIKÁT | REI 180 | 1752HWa0000009552 | m3 | Celá stěna | Stávající | Zednické práce | PLYNOSILIKÁT |  | 1752Stě0000009677 | m3 | Stěna | 0.541 | 0.3 | 2.046 | 2.046 | 0.614 | 0.62 | 0.614 | 0.186 | 3.3 | Pset_WallCommon - AcousticRating: 48 dB
ZELEZOBETONOVÁ KCE | Půdorys 4.NP | ZELEZOBETONOVÁ KCE 0.3 m |  | ZELEZOBETONOVÁ KCE | A | 1752HWa0000009550 | m3 | Celá stěna | Stávající | Betonářské práce | ZELEZOBETONOVÁ KCE | no | 1752Stě0000010250 | m3 | Stěna | 0 | 0.3 | 51.48 | 43.38 | 15.444 | 15.6 | 13.014 | 4.68 | 3.3
ZDIVO Z CDm | Půdorys 4.NP | ZDIVO Z CDm 0.2 m | 1 | ZDIVO Z CDm | A | 1752HWa0000019295 | m3 | Celá stěna | Stávající | Zednické práce | ZDIVO Z CDm | yes | 1752Stě0000019296 | m3 | Stěna | 0 | 0.2 | 0.671 | 0.671 | 0.134 | 0.22 | 0.134 | 0.044 | 3.05
ZDIVO Z CDm | Půdorys 4.NP | ZDIVO Z CDm 0.125 m | 1 | ZDIVO Z CDm | A | 1752HWa0000009926 | m3 | Celá stěna | Stávající | Zednické práce | ZDIVO Z CDm | yes | 1752Stě0000010318 | m3 | Stěna | 0 | 0.125 | 0.702 | 0.702 | 0.088 | 0.23 | 0.088 | 0.029 | 3.05
ZDIVO Z CDm | Půdorys 4.NP | ZDIVO Z CDm 0.125 m | 1 | ZDIVO Z CDm | A | 1752HWa0000009909 | m3 | Celá stěna | Stávající | Zednické práce | ZDIVO Z CDm | yes | 1752Stě0000009941 | m3 | Stěna | 0 | 0.125 | 11.132 | 8.002 | 1.392 | 3.65 | 1 | 0.456 | 3.05
ZDIVO Z CDm | Půdorys 4.NP | ZDIVO Z CDm 0.125 m | 1 | ZDIVO Z CDm | A | 1752HWa0000009907 | m3 | Celá stěna | Stávající | Zednické práce | ZDIVO Z CDm | yes | 1752Stě0000009938 | m3 | Stěna | 0 | 0.125 | 7.091 | 7.091 | 0.886 | 2.325 | 0.886 | 0.291 | 3.05
ZDIVO Z CDm | Půdorys 4.NP | ZDIVO Z CDm 0.125 m | 1 | ZDIVO Z CDm | A | 1752HWa0000009908 | m3 | Celá stěna | Stávající | Zednické práce | ZDIVO Z CDm | yes | 1752Stě0000010322 | m3 | Stěna | 0 | 0.125 | 4.27 | 4.27 | 0.534 | 1.4 | 0.534 | 0.175 | 3.05
ZDIVO Z CDm | Půdorys 4.NP | ZDIVO Z CDm 0.125 m | 1 | ZDIVO Z CDm | A | 1752HWa0000009930 | m3 | Celá stěna | Stávající | Zednické práce | ZDIVO Z CDm | yes | 1752Stě0000010320 | m3 | Stěna | 0 | 0.125 | 14.03 | 14.03 | 1.754 | 4.6 | 1.754 | 0.575 | 3.05
ZDIVO Z CDm | Půdorys 4.NP | ZDIVO Z CDm 0.125 m | 1 | ZDIVO Z CDm | A | 1752HWa0000009906 | m3 | Celá stěna | Stávající | Zednické práce | ZDIVO Z CDm | yes | 1752Stě0000010316 | m3 | Stěna | 0 | 0.125 | 9.973 | 10.065 | 1.247 | 3.27 | 1.247 | 0.409 | 3.05
ZDIVO Z CDm | Půdorys 4.NP | ZDIVO Z CDm 0.125 m | 1 | ZDIVO Z CDm | A | 1752HWa0000014903 | m3 | Celá stěna | Stávající | Zednické práce | ZDIVO Z CDm |  | 1752Stě0000014904 | m3 | Stěna | 0 | 0.125 | 0.915 | 0.915 | 0.114 | 0.3 | 0.114 | 0.037 | 3.05
ZDIVO Z CDm | Půdorys 4.NP | ZDIVO Z CDm 0.125 m | 1 | ZDIVO Z CDm | A | 1752HWa0000015369 | m3 | Celá stěna | Stávající | Zednické práce | ZDIVO Z CDm | yes | 1752Stě0000015370 | m3 | Stěna | 0 | 0.125 | 1.586 | 1.586 | 0.198 | 0.52 | 0.198 | 0.065 | 3.05
ZDIVO Z CDm | Půdorys 4.NP | ZDIVO Z CDm 0.125 m | 1 | ZDIVO Z CDm | A | 1752HWa0000009893 | m3 | Celá stěna | Stávající | Zednické práce | ZDIVO Z CDm | yes | 1752Stě0000009897 | m3 | Stěna | 0 | 0.125 | 2.364 | 2.364 | 0.295 | 0.775 | 0.295 | 0.097 | 3.05
ZDIVO Z CDm | Půdorys 4.NP | ZDIVO Z CDm 0.125 m | 1 | ZDIVO Z CDm | A | 1752HWa0000009891 | m3 | Celá stěna | Stávající | Zednické práce | ZDIVO Z CDm | yes | 1752Stě0000009903 | m3 | Stěna | 0 | 0.125 | 0.762 | 0.763 | 0.095 | 0.25 | 0.095 | 0.031 | 3.05
ZDIVO Z CDm | Půdorys 4.NP | ZDIVO Z CDm 0.125 m | 1 | ZDIVO Z CDm | A | 1752HWa0000019070 | m3 | Celá stěna | Stávající | Zednické práce | ZDIVO Z CDm | yes | 1752Stě0000019071 | m3 | Stěna | 0 | 0.125 | 5.856 | 5.856 | 0.732 | 1.92 | 0.732 | 0.24 | 3.05
ZDIVO Z CDm | Půdorys 4.NP | ZDIVO Z CDm 0.125 m | 1 | ZDIVO Z CDm | A | 1752HWa0000019059 | m3 | Celá stěna | Stávající | Zednické práce | ZDIVO Z CDm | yes | 1752Stě0000019060 | m3 | Stěna | 0 | 0.125 | 1.525 | 1.525 | 0.191 | 0.5 | 0.191 | 0.063 | 3.05
ZDIVO Z CDm | Půdorys 4.NP | ZDIVO Z CDm 0.125 m | 1 | ZDIVO Z CDm | A | 1752HWa0000009757 | m3 | Celá stěna | Stávající | Zednické práce | ZDIVO Z CDm | yes | 1752Stě0000009899 | m3 | Stěna | 0 | 0.125 | 4.041 | 3.551 | 0.505 | 1.325 | 0.444 | 0.166 | 3.05
ZDIVO Z CDm | Půdorys 4.NP | ZDIVO Z CDm 0.125 m | 1 | ZDIVO Z CDm | A | 1752HWa0000009522 | m3 | Celá stěna | Stávající | Zednické práce | ZDIVO Z CDm | yes | 1752Stě0000009901 | m3 | Stěna | 0 | 0.125 | 1.525 | 1.525 | 0.191 | 0.5 | 0.191 | 0.062 | 3.05
ZDIVO Z CDm | Půdorys 4.NP | ZDIVO Z CDm 0.125 m | 1 | ZDIVO Z CDm | A | 1752HWa0000019146 | m3 | Celá stěna | Stávající | Zednické práce | ZDIVO Z CDm | yes | 1752Stě0000019147 | m3 | Stěna | 0 | 0.125 | 3.126 | 3.126 | 0.391 | 1.025 | 0.391 | 0.128 | 3.05
ZDIVO Z CDm | Půdorys 4.NP | ZDIVO Z CDm 0.1 m | 1 | ZDIVO Z CDm | A | 1752HWa0000019384 | m3 | Celá stěna | Stávající | Zednické práce | ZDIVO Z CDm |  | 1752Stě0000019385 | m3 | Stěna | 0 | 0.1 | 9.379 | 7.359 | 0.938 | 3.075 | 0.736 | 0.308 | 3.05
ZELEZOBETONOVÁ KCE | Půdorys 4.NP | ZELEZOBETONOVÁ KCE 0.2 m |  | ZELEZOBETONOVÁ KCE | A | 1752HWa0000009509 | m3 | Celá stěna | Stávající | Betonářské práce | ZELEZOBETONOVÁ KCE | yes | 1752Stě0000009701 | m3 | Stěna | 0 | 0.2 | 14.64 | 14.64 | 2.928 | 4.8 | 2.928 | 0.96 | 3.05
ZELEZOBETONOVÁ KCE | Půdorys 4.NP | ZELEZOBETONOVÁ KCE 0.2 m |  | ZELEZOBETONOVÁ KCE | A | 1752HWa0000009511 | m3 | Celá stěna | Stávající | Betonářské práce | ZELEZOBETONOVÁ KCE |  | 1752Stě0000009733 | m3 | Stěna | 0 | 0.2 | 4.575 | 4.575 | 0.915 | 1.5 | 0.915 | 0.3 | 3.05
ZELEZOBETONOVÁ KCE | Půdorys 4.NP | ZELEZOBETONOVÁ KCE 0.2 m |  | ZELEZOBETONOVÁ KCE | A | 1752HWa0000009507 | m3 | Celá stěna | Stávající | Betonářské práce | ZELEZOBETONOVÁ KCE |  | 1752Stě0000010324 | m3 | Stěna | 0 | 0.2 | 5.795 | 5.795 | 1.159 | 1.9 | 1.159 | 0.38 | 3.05
ZELEZOBETONOVÁ KCE | Půdorys 4.NP | ZELEZOBETONOVÁ KCE 0.2 m |  | ZELEZOBETONOVÁ KCE | A | 1752HWa0000019284 | m3 | Celá stěna | Stávající | Betonářské práce | ZELEZOBETONOVÁ KCE |  | 1752Stě0000019286 | m3 | Stěna | 0 | 0.2 | 5.795 | 5.795 | 1.159 | 1.9 | 1.159 | 0.38 | 3.05
ZELEZOBETONOVÁ KCE | Půdorys 4.NP | ZELEZOBETONOVÁ KCE 0.2 m |  | ZELEZOBETONOVÁ KCE | A | 1752HWa0000007979 | m3 | Celá stěna | Stávající | Betonářské práce | ZELEZOBETONOVÁ KCE |  | 1752Stě0000009689 | m3 | Stěna | 0 | 0.2 | 14.64 | 14.64 | 2.928 | 4.8 | 2.928 | 0.96 | 3.05
ZELEZOBETONOVÁ KCE | Půdorys 4.NP | ZELEZOBETONOVÁ KCE 0.2 m |  | ZELEZOBETONOVÁ KCE | A | 1752HWa0000019199 | m3 | Celá stěna | Stávající | Betonářské práce | ZELEZOBETONOVÁ KCE |  | 1752Stě0000019201 | m3 | Stěna | 0 | 0.2 | 14.64 | 14.64 | 2.928 | 4.8 | 2.928 | 0.96 | 3.05
ZDIVO Z CDm | Půdorys 4.NP | ZDIVO Z CDm 0.22 m |  | ZDIVO Z CDm | A | 1752HWa0000014725 | m3 | Celá stěna | Stávající | Zednické práce | ZDIVO Z CDm |  | 1752Stě0000014726 | m3 | Stěna | 0 | 0.22 | 4.651 | 4.651 | 1.023 | 1.525 | 1.023 | 0.336 | 3.05
ZELEZOBETONOVÁ KCE | Půdorys 4.NP | ZELEZOBETONOVÁ KCE 0.2 m |  | ZELEZOBETONOVÁ KCE | A | 1752HWa0000009525 | m3 | Celá stěna | Stávající | Betonářské práce | ZELEZOBETONOVÁ KCE | yes | 1752Stě0000009905 | m3 | Stěna | 0 | 0.2 | 7.32 | 7.32 | 1.464 | 2.4 | 1.464 | 0.48 | 3.05
PLYNOSILIKÁT | Půdorys 4.NP | PLYNOSILIKÁT 0.2 m | 1 | PLYNOSILIKÁT | REI 180 | 1752HWa0000014584 | m3 | Celá stěna | Stávající | Zednické práce | PLYNOSILIKÁT |  | 1752Stě0000014585 | m3 | Stěna | 0.541 | 0.2 | 8.1 | 8.1 | 1.62 | 3.6 | 1.62 | 0.72 | 2.25 | Pset_WallCommon - AcousticRating: 48 dB
ZDIVO Z CDm | Půdorys 4.NP | ZDIVO Z CDm 0.1 m | 1 | ZDIVO Z CDm | A | 1752HWa0798426806 | m3 | Celá stěna | Stávající | Zednické práce | ZDIVO Z CDm | yes | 1752Stě0798426807 | m3 | Stěna | 0 | 0.1 | 0.839 | 0.839 | 0.084 | 0.275 | 0.084 | 0.027 | 3.05
ZDIVO Z CDm | Půdorys 4.NP | ZDIVO Z CDm 0.125 m | 1 | ZDIVO Z CDm | A | 1752HWa0000019047 | m3 | Celá stěna | Stávající | Zednické práce | ZDIVO Z CDm | yes | 1752Stě0000019048 | m3 | Stěna | 0 | 0.125 | 12.398 | 12.886 | 1.55 | 4.065 | 1.55 | 0.508 | 3.05
ZDIVO Z CDm | Půdorys 4.NP | ZDIVO Z CDm 0.125 m | 1 | ZDIVO Z CDm | A | 1752HWa0000019165 | m3 | Celá stěna | Stávající | Zednické práce | ZDIVO Z CDm | yes | 1752Stě0000019166 | m3 | Stěna | 0 | 0.125 | 1.22 | 1.22 | 0.153 | 0.4 | 0.153 | 0.05 | 3.05
ZDIVO Z CDm | Půdorys 4.NP | ZDIVO Z CDm 0.125 m | 1 | ZDIVO Z CDm | A | 1752HWa0000010485 | m3 | Celá stěna | Stávající | Zednické práce | ZDIVO Z CDm | yes | 1752Stě0000010491 | m3 | Stěna | 0 | 0.125 | 3.187 | 3.431 | 0.398 | 1.045 | 0.398 | 0.131 | 3.05
ZDIVO Z CDm | Půdorys 4.NP | ZDIVO Z CDm 0.125 m | 1 | ZDIVO Z CDm | A | 1752HWa0000010483 | m3 | Celá stěna | Stávající | Zednické práce | ZDIVO Z CDm | yes | 1752Stě0000010505 | m3 | Stěna | 0 | 0.125 | 30.5 | 27.369 | 3.813 | 10 | 3.421 | 1.25 | 3.05
ZDIVO Z CDm | Půdorys 4.NP | ZDIVO Z CDm 0.125 m | 1 | ZDIVO Z CDm | A | 1752HWa0798426055 | m3 | Celá stěna | Stávající | Zednické práce | ZDIVO Z CDm | yes | 1752Stě0798426056 | m3 | Stěna | 0 | 0.125 | 2.669 | 2.669 | 0.334 | 0.875 | 0.334 | 0.109 | 3.05
ZELEZOBETONOVÁ KCE | Půdorys 4.NP | ZELEZOBETONOVÁ KCE 0.2 m | 1 | ZELEZOBETONOVÁ KCE | A | 1752HWa0000009494 | m3 | Celá stěna | Stávající | Betonářské práce | ZELEZOBETONOVÁ KCE | yes | 1752Stě0000009707 | m3 | Stěna | 0 | 0.2 | 10.98 | 10.98 | 2.196 | 3.6 | 2.196 | 0.72 | 3.05
ZELEZOBETONOVÁ KCE | Půdorys 4.NP | ZELEZOBETONOVÁ KCE 0.2 m | 1 | ZELEZOBETONOVÁ KCE | A | 1752HWa0798426487 | m3 | Celá stěna | Stávající | Betonářské práce | ZELEZOBETONOVÁ KCE | yes | 1752Stě0798426489 | m3 | Stěna | 0 | 0.2 | 12.2 | 12.2 | 2.44 | 4 | 2.44 | 0.8 | 3.05
ZELEZOBETONOVÁ KCE | Půdorys 4.NP | ZELEZOBETONOVÁ KCE 0.2 m | 1 | ZELEZOBETONOVÁ KCE | A | 1752HWa0000007980 | m3 | Celá stěna | Stávající | Betonářské práce | ZELEZOBETONOVÁ KCE | yes | 1752Stě0000009735 | m3 | Stěna | 0 | 0.2 | 10.98 | 10.98 | 2.196 | 3.6 | 2.196 | 0.72 | 3.05
ZELEZOBETONOVÁ KCE | Půdorys 4.NP | ZELEZOBETONOVÁ KCE 0.3 m | 1 | ZELEZOBETONOVÁ KCE | A | 1752HWa0000007965 | m3 | Celá stěna | Stávající | Betonářské práce | ZELEZOBETONOVÁ KCE |  | 1752Stě0000010339 | m3 | Stěna | 0 | 0.3 | 3.465 | 3.465 | 1.04 | 1.05 | 1.04 | 0.315 | 3.3
ZELEZOBETONOVÁ KCE | Půdorys 4.NP | ZELEZOBETONOVÁ KCE 0.3 m | 1 | ZELEZOBETONOVÁ KCE | A | 1752HWa0000007977 | m3 | Celá stěna | Stávající | Betonářské práce | ZELEZOBETONOVÁ KCE |  | 1752Stě0000010349 | m3 | Stěna | 0 | 0.3 | 3.465 | 3.465 | 1.04 | 1.05 | 1.04 | 0.315 | 3.3
ZELEZOBETONOVÁ KCE | Půdorys 4.NP | ZELEZOBETONOVÁ KCE 0.3 m | 1 | ZELEZOBETONOVÁ KCE | A | 1752HWa0000009539 | m3 | Celá stěna | Stávající | Betonářské práce | ZELEZOBETONOVÁ KCE |  | 1752Stě0000010576 | m3 | Stěna | 0 | 0.3 | 3.366 | 3.366 | 1.01 | 1.02 | 1.01 | 0.306 | 3.3
ZELEZOBETONOVÁ KCE | Půdorys 4.NP | ZELEZOBETONOVÁ KCE 0.3 m | 1 | ZELEZOBETONOVÁ KCE | A | 1752HWa0000009747 | m3 | Celá stěna | Stávající | Betonářské práce | ZELEZOBETONOVÁ KCE | no | 1752Stě0000010551 | m3 | Stěna | 0 | 0.3 | 3.366 | 3.366 | 1.01 | 1.02 | 1.01 | 0.306 | 3.3
PLYNOSILIKÁT | Půdorys 4.NP | PLYNOSILIKÁT 0.32 m | 1 | PLYNOSILIKÁT | REI 180 | 1752HWa0000010154 | m3 | Celá stěna | Stávající | Zednické práce | PLYNOSILIKÁT | no | 1752Stě0000010574 | m3 | Stěna | 0.541 | 0.32 | 51.48 | 22.28 | 16.474 | 15.6 | 7.13 | 4.992 | 3.3 | Pset_WallCommon - AcousticRating: 48 dB
ZELEZOBETONOVÁ KCE | Půdorys 4.NP | ZELEZOBETONOVÁ KCE 0.2 m | 1 | ZELEZOBETONOVÁ KCE | A | 1752HWa0000009491 | m3 | Celá stěna | Stávající | Betonářské práce | ZELEZOBETONOVÁ KCE | yes | 1752Stě0000009709 | m3 | Stěna | 0 | 0.2 | 15.25 | 15.25 | 3.05 | 5 | 3.05 | 1 | 3.05
ZELEZOBETONOVÁ KCE | Půdorys 4.NP | ZELEZOBETONOVÁ KCE 0.3 m | 1 | ZELEZOBETONOVÁ KCE | A | 1752HWa0000007966 | m3 | Celá stěna | Stávající | Betonářské práce | ZELEZOBETONOVÁ KCE |  | 1752Stě0000010115 | m3 | Stěna | 0 | 0.3 | 18.645 | 18.645 | 5.594 | 5.65 | 5.594 | 1.695 | 3.3
ZDIVO Z CDm | Půdorys 4.NP | ZDIVO Z CDm 0.48 m | 1 | ZDIVO Z CDm | A | 1752HWa0798427237 | m3 | Celá stěna | Stávající | Zednické práce | ZDIVO Z CDm |  | 1752Stě0798427241 | m3 | Stěna | 0 | 0.269 | 1.584 | 1.584 | 0.426 | 0.48 | 0.426 | 0.129 | 3.3
ZDIVO Z CDm | Půdorys 4.NP | ZDIVO Z CDm 0.48 m | 1 | ZDIVO Z CDm | A | 1752HWa0798427242 | m3 | Celá stěna | Stávající | Zednické práce | ZDIVO Z CDm |  | 1752Stě0798427246 | m3 | Stěna | 0 | 0.48 | 1.444 | 1.32 | 0.693 | 0.438 | 0.693 | 0.21 | 3.3
ZDIVO Z CDm | Půdorys 4.NP | ZDIVO Z CDm 0.125 m |  | ZDIVO Z CDm | A | 1752HWa0000014652 | m3 | Celá stěna | Stávající | Zednické práce | ZDIVO Z CDm | no | 1752Stě0000014653 | m3 | Stěna | 0 | 0.125 | 0.479 | 0.479 | 0.06 | 0.33 | 0.06 | 0.041 | 1.45
ZDIVO Z CDm | Půdorys 4.NP | ZDIVO Z CDm 0.2 m |  | ZDIVO Z CDm | A | 1752HWa0000014662 | m3 | Celá stěna | Stávající | Zednické práce | ZDIVO Z CDm | no | 1752Stě0000014663 | m3 | Stěna | 0 | 0.2 | 0.58 | 0.58 | 0.116 | 0.4 | 0.116 | 0.08 | 1.45
ZELEZOBETONOVÁ KCE | Půdorys 4.NP | ZELEZOBETONOVÁ KCE 0.2 m |  | ZELEZOBETONOVÁ KCE | A | 1752HWa0000014497 | m3 | Celá stěna | Stávající | Betonářské práce | ZELEZOBETONOVÁ KCE | yes | 1752Stě0000014499 | m3 | Stěna | 0 | 0.2 | 2.61 | 2.61 | 0.522 | 1.8 | 0.522 | 0.36 | 1.45
ZDIVO Z CDm | Půdorys 4.NP | ZDIVO Z CDm 0.4 m |  | ZDIVO Z CDm | A | 1752HWa0000014613 | m3 | Celá stěna | Stávající | Zednické práce | ZDIVO Z CDm | no | 1752Stě0000014614 | m3 | Stěna | 0 | 0.4 | 0.754 | 0.725 | 0.302 | 0.52 | 0.29 | 0.208 | 1.45
ZDIVO Z CDm | Půdorys 4.NP | ZDIVO Z CDm 0.125 m |  | ZDIVO Z CDm | A | 1752HWa0798427768 | m3 | Celá stěna | Stávající | Zednické práce | ZDIVO Z CDm | yes | 1752Stě0798427769 | m3 | Stěna | 0 | 0.125 | 6.768 | 4.95 | 0.846 | 2.4 | 0.619 | 0.3 | 2.82
ZELEZOBETONOVÁ KCE | Půdorys 4.NP | ZELEZOBETONOVÁ KCE 0.3 m | 1 | ZELEZOBETONOVÁ KCE | A | 1752HWa0000009531 | m3 | Celá stěna | Stávající | Betonářské práce | ZELEZOBETONOVÁ KCE |  | 1752Stě0000010123 | m3 | Stěna | 0 | 0.3 | 3.96 | 3.96 | 1.188 | 1.2 | 1.188 | 0.36 | 3.3
ZDIVO Z CDm | Půdorys 4.NP | EPS 0.1 m, ZDIVO Z CDm 0.3 m |  | ZDIVO Z CDm | A | 1752HWa0000009534 | m3 | Celá stěna | Stávající | Zateplovací systémy | EPS |  | 1752Stě0000010150 | m2 | Stěna | 0 | 0.4 | 1.708 | 1.709 | 0.632 | 0.955 | 0.632 | 0.372 | 1.7 | NEMSOK - Object Layer Attributes #2, 2D interakce: yes; Object Layer Attributes #2, Status: Stávající; Object Layer Attributes #2, Práce: Zednické práce; Object Layer Attributes #2, Materiál: ZDIVO Z CDm; Object Layer Attributes #2, Allright_Stavebni_dil_ID: 1752Stě0798428038; Object Layer Attributes #2, Jednotka: m3; Object Layer Attributes #2, Název_objektu: Stěna
PLYNOSILIKÁT | Půdorys 4.NP | EPS 0.1 m, PLYNOSILIKÁT 0.3 m | 1 | PLYNOSILIKÁT | REI 180 | 1752HWa0798427523 | m3 | Celá stěna | Stávající | Zateplovací systémy | EPS |  | 1752Stě0798427525 | m2 | Stěna | 0.541 | 0.4 | 4.25 | 4.25 | 1.547 | 2.35 | 1.547 | 0.91 | 1.7 | NEMSOK - Object Layer Attributes #2, 2D interakce: yes; Object Layer Attributes #2, Status: Stávající; Object Layer Attributes #2, Práce: Zednické práce; Object Layer Attributes #2, Materiál: PLYNOSILIKÁT; Object Layer Attributes #2, Allright_Stavebni_dil_ID: 1752Stě0798428107; Object Layer Attributes #2, Jednotka: m3; Object Layer Attributes #2, Název_objektu: Stěna; Pset_WallCommon - AcousticRating: 48 dB
PLYNOSILIKÁT | Půdorys 4.NP | EPS 0.1 m, PLYNOSILIKÁT 0.3 m | 1 | PLYNOSILIKÁT | REI 180 | 1752HWa0000014592 | m3 | Celá stěna | Stávající | Zateplovací systémy | EPS |  | 1752Stě0000014593 | m2 | Stěna | 0.541 | 0.4 | 8.349 | 8.349 | 3.34 | 3.4 | 3.34 | 1.36 | 2.456 | NEMSOK - Object Layer Attributes #2, 2D interakce: yes; Object Layer Attributes #2, Status: Stávající; Object Layer Attributes #2, Práce: Zednické práce; Object Layer Attributes #2, Materiál: PLYNOSILIKÁT; Object Layer Attributes #2, Allright_Stavebni_dil_ID: 1752Stě0798428152; Object Layer Attributes #2, Jednotka: m3; Object Layer Attributes #2, Název_objektu: Stěna; Pset_WallCommon - AcousticRating: 48 dB
ZELEZOBETONOVÁ KCE | Půdorys 4.NP | EPS 0.1 m, ZELEZOBETONOVÁ KCE 0.3 m | 1 | ZELEZOBETONOVÁ KCE | A | 1752HWa0000009536 | m3 | Celá stěna | Stávající | Zateplovací systémy | EPS |  | 1752Stě0000009679 | m2 | Stěna | 0 | 0.4 | 8.571 | 8.571 | 3.329 | 2.45 | 3.329 | 1.01 | 3.297 | NEMSOK - Object Layer Attributes #2, 2D interakce: yes; Object Layer Attributes #2, Status: Stávající; Object Layer Attributes #2, Práce: Betonářské práce; Object Layer Attributes #2, Materiál: ZELEZOBETONOVÁ KCE; Object Layer Attributes #2, Allright_Stavebni_dil_ID: 1752Stě0798428189; Object Layer Attributes #2, Jednotka: m3; Object Layer Attributes #2, Název_objektu: Stěna
ZDIVO Z CDm | Půdorys 4.NP | ZDIVO Z CDm 0.125 m | 1 | ZDIVO Z CDm | A | 1752HWa0798429058 | m3 | Celá stěna | Stávající | Zednické práce | ZDIVO Z CDm | yes | 1752Stě0798429075 | m3 | Stěna | 0 | 0.125 | 5.109 | 4.389 | 0.639 | 1.675 | 0.549 | 0.209 | 3.05
ZDIVO Z CDm | Půdorys 4.NP | ZDIVO Z CDm 0.125 m | 1 | ZDIVO Z CDm | A | 1752HWa0798429059 | m3 | Celá stěna | Stávající | Zednické práce | ZDIVO Z CDm | yes | 1752Stě0798429080 | m3 | Stěna | 0 | 0.125 | 3.965 | 3.965 | 0.496 | 1.3 | 0.496 | 0.162 | 3.05
ZDIVO Z CDm | Půdorys 4.NP | ZDIVO Z CDm 0.25 m | 1 | ZDIVO Z CDm | A | 1752HWa0798429060 | m3 | Celá stěna | Stávající | Zednické práce | ZDIVO Z CDm | yes | 1752Stě0798429085 | m3 | Stěna | 0 | 0.25 | 10.065 | 10.065 | 2.516 | 3.3 | 2.516 | 0.825 | 3.05
ZDIVO Z CDm | Půdorys 4.NP | ZDIVO Z CDm 0.125 m | 1 | ZDIVO Z CDm | A | 1752HWa0798429061 | m3 | Celá stěna | Stávající | Zednické práce | ZDIVO Z CDm | yes | 1752Stě0798429087 | m3 | Stěna | 0 | 0.125 | 3.965 | 3.965 | 0.496 | 1.3 | 0.496 | 0.162 | 3.05
ZDIVO Z CDm | Půdorys 4.NP | ZDIVO Z CDm 0.125 m | 1 | ZDIVO Z CDm | A | 1752HWa0798429068 | m3 | Celá stěna | Stávající | Zednické práce | ZDIVO Z CDm | yes | 1752Stě0798429083 | m3 | Stěna | 0 | 0.125 | 10.065 | 10.065 | 1.258 | 3.3 | 1.258 | 0.413 | 3.05
ZELEZOBETONOVÁ KCE | Půdorys 4.NP | EPS 0.1 m, ZELEZOBETONOVÁ KCE 0.3 m | 1 | ZELEZOBETONOVÁ KCE | A | 1752HWa0000007975 | m3 | Celá stěna | Stávající | Zateplovací systémy | EPS | no | 1752Stě0000009881 | m2 | Stěna | 0 | 0.4 | 11.814 | 11.814 | 4.448 | 3.44 | 4.448 | 1.348 | 3.3 | NEMSOK - Object Layer Attributes #2, 2D interakce: yes; Object Layer Attributes #2, Status: Stávající; Object Layer Attributes #2, Práce: Betonářské práce; Object Layer Attributes #2, Materiál: ZELEZOBETONOVÁ KCE; Object Layer Attributes #2, Allright_Stavebni_dil_ID: 1752Stě0798429126; Object Layer Attributes #2, Jednotka: m3; Object Layer Attributes #2, Název_objektu: Stěna; Object Layer Attributes #2, Staticky nosná konstrukce: no
ZELEZOBETONOVÁ KCE | Půdorys 4.NP | EPS 0.1 m, ZELEZOBETONOVÁ KCE 0.3 m | 1 | ZELEZOBETONOVÁ KCE | A | 1752HWa0000007969 | m3 | Celá stěna | Stávající | Zateplovací systémy | EPS | no | 1752Stě0000010103 | m2 | Stěna | 0 | 0.4 | 11.814 | 11.814 | 4.448 | 3.44 | 4.448 | 1.348 | 3.3 | NEMSOK - Object Layer Attributes #2, 2D interakce: yes; Object Layer Attributes #2, Status: Stávající; Object Layer Attributes #2, Práce: Betonářské práce; Object Layer Attributes #2, Materiál: ZELEZOBETONOVÁ KCE; Object Layer Attributes #2, Allright_Stavebni_dil_ID: 1752Stě0798429169; Object Layer Attributes #2, Jednotka: m3; Object Layer Attributes #2, Název_objektu: Stěna; Object Layer Attributes #2, Staticky nosná konstrukce: no
ZELEZOBETONOVÁ KCE | Půdorys 4.NP | EPS 0.1 m, ZELEZOBETONOVÁ KCE 0.3 m |  | ZELEZOBETONOVÁ KCE | A | 1752HWa0798429936 | m3 | Celá stěna | Stávající | Zateplovací systémy | EPS | no | 1752Stě0798429949 | m2 | Stěna | 0 | 0.4 | 7.83 | 5.215 | 3.119 | 2.53 | 2.057 | 0.978 | 3.3 | NEMSOK - Object Layer Attributes #2, 2D interakce: yes; Object Layer Attributes #2, Status: Stávající; Object Layer Attributes #2, Práce: Betonářské práce; Object Layer Attributes #2, Materiál: ZELEZOBETONOVÁ KCE; Object Layer Attributes #2, Allright_Stavebni_dil_ID: 1752Stě0798429948; Object Layer Attributes #2, Jednotka: m3; Object Layer Attributes #2, Název_objektu: Stěna; Object Layer Attributes #2, Staticky nosná konstrukce: no
ZELEZOBETONOVÁ KCE | Půdorys 4.NP | EPS 0.15 m, ZELEZOBETONOVÁ KCE 0.3 m |  | ZELEZOBETONOVÁ KCE | A | 1752HWa0798429846 | m3 | Celá stěna | Stávající | Zateplovací systémy | EPS | no | 1752Stě0798429868 | m2 | Stěna | 0 | 0.45 | 28.28 | 28.28 | 12.241 | 8.08 | 12.19 | 3.636 | 3.5 | NEMSOK - Object Layer Attributes #2, 2D interakce: yes; Object Layer Attributes #2, Status: Stávající; Object Layer Attributes #2, Práce: Betonářské práce; Object Layer Attributes #2, Materiál: ZELEZOBETONOVÁ KCE; Object Layer Attributes #2, Allright_Stavebni_dil_ID: 1752Stě0798429869; Object Layer Attributes #2, Jednotka: m3; Object Layer Attributes #2, Název_objektu: Stěna; Object Layer Attributes #2, Staticky nosná konstrukce: no
ZELEZOBETONOVÁ KCE | Půdorys 4.NP | EPS 0.1 m, ZELEZOBETONOVÁ KCE 0.3 m |  | ZELEZOBETONOVÁ KCE | A | 1752HWa0000007971 | m3 | Celá stěna | Stávající | Zateplovací systémy | EPS | no | 1752Stě0000010121 | m2 | Stěna | 0 | 0.4 | 11.41 | 9.479 | 4.071 | 3.11 | 3.254 | 1.214 | 3.5 | NEMSOK - Object Layer Attributes #2, 2D interakce: yes; Object Layer Attributes #2, Status: Stávající; Object Layer Attributes #2, Práce: Betonářské práce; Object Layer Attributes #2, Materiál: ZELEZOBETONOVÁ KCE; Object Layer Attributes #2, Allright_Stavebni_dil_ID: 1752Stě0798429214; Object Layer Attributes #2, Jednotka: m3; Object Layer Attributes #2, Název_objektu: Stěna; Object Layer Attributes #2, Staticky nosná konstrukce: no
ZDIVO Z CDm | Půdorys 4.NP | EPS 0.1 m, ZDIVO Z CDm 0.5 m |  | ZDIVO Z CDm | A | 1752HWa0000000008 | m3 | Celá stěna | Stávající | Zateplovací systémy | EPS | no | 1752Stě0000000050 | m2 | Stěna | 0 | 0.6 | 13.44 | 13.44 | 7.391 | 4.15 | 7.391 | 2.47 | 3.2 | NEMSOK - Object Layer Attributes #2, 2D interakce: yes; Object Layer Attributes #2, Status: Stávající; Object Layer Attributes #2, Práce: Zednické práce; Object Layer Attributes #2, Materiál: ZDIVO Z CDm; Object Layer Attributes #2, Allright_Stavebni_dil_ID: 1752Stě0798430322; Object Layer Attributes #2, Jednotka: m3; Object Layer Attributes #2, Název_objektu: Stěna; Object Layer Attributes #2, Staticky nosná konstrukce: yes
ZDIVO Z CDm | Půdorys 4.NP | EPS 0.1 m, ZDIVO Z CDm 0.5 m | 1 | ZDIVO Z CDm | A | 1752HWa0000000016 | m3 | Celá stěna | Stávající | Zateplovací systémy | EPS | no | 1752Stě0000000026 | m2 | Stěna | 0 | 0.6 | 27.68 | 27.68 | 14.642 | 8.35 | 14.642 | 4.89 | 3.2 | NEMSOK - Object Layer Attributes #2, 2D interakce: yes; Object Layer Attributes #2, Status: Stávající; Object Layer Attributes #2, Práce: Zednické práce; Object Layer Attributes #2, Materiál: ZDIVO Z CDm; Object Layer Attributes #2, Allright_Stavebni_dil_ID: 1752Stě0798430401; Object Layer Attributes #2, Jednotka: m3; Object Layer Attributes #2, Název_objektu: Stěna; Object Layer Attributes #2, Staticky nosná konstrukce: yes
ZDIVO Z CDm | Půdorys 4.NP | EPS 0.1 m, ZDIVO Z CDm 0.5 m | 1 | ZDIVO Z CDm | A | 1752HWa0000000002 | m3 | Celá stěna | Stávající | Zateplovací systémy | EPS | no | 1752Stě0000000036 | m2 | Stěna | 0 | 0.6 | 13.12 | 13.12 | 6.622 | 3.85 | 6.622 | 2.21 | 3.2 | NEMSOK - Object Layer Attributes #2, 2D interakce: yes; Object Layer Attributes #2, Status: Stávající; Object Layer Attributes #2, Práce: Zednické práce; Object Layer Attributes #2, Materiál: ZDIVO Z CDm; Object Layer Attributes #2, Allright_Stavebni_dil_ID: 1752Stě0798430441; Object Layer Attributes #2, Jednotka: m3; Object Layer Attributes #2, Název_objektu: Stěna; Object Layer Attributes #2, Staticky nosná konstrukce: yes
ZDIVO Z CDm | Půdorys 4.NP | EPS 0.1 m, ZDIVO Z CDm 0.5 m |  | ZDIVO Z CDm | A | 1752HWa0000004734 | m3 | Celá stěna | Stávající | Zateplovací systémy | EPS | no | 1752Stě0000004736 | m2 | Stěna | 0 | 0.6 | 8.178 | 8.178 | 4.673 | 2.95 | 4.673 | 1.79 | 2.82 | NEMSOK - Object Layer Attributes #2, 2D interakce: yes; Object Layer Attributes #2, Status: Stávající; Object Layer Attributes #2, Práce: Zednické práce; Object Layer Attributes #2, Materiál: ZDIVO Z CDm; Object Layer Attributes #2, Allright_Stavebni_dil_ID: 1752Stě0798430565; Object Layer Attributes #2, Jednotka: m3; Object Layer Attributes #2, Název_objektu: Stěna; Object Layer Attributes #2, Staticky nosná konstrukce: yes
ZDIVO Z CDm | Půdorys 4.NP | EPS 0.1 m, ZDIVO Z CDm 0.5 m |  | ZDIVO Z CDm | A | 1752HWa0000000006 | m3 | Celá stěna | Stávající | Zateplovací systémy | EPS | no | 1752Stě0000000046 | m2 | Stěna | 0 | 0.6 | 10.152 | 10.152 | 5.384 | 3.5 | 5.384 | 2.06 | 2.82 | NEMSOK - Object Layer Attributes #2, 2D interakce: yes; Object Layer Attributes #2, Status: Stávající; Object Layer Attributes #2, Práce: Zednické práce; Object Layer Attributes #2, Materiál: ZDIVO Z CDm; Object Layer Attributes #2, Allright_Stavebni_dil_ID: 1752Stě0798430517; Object Layer Attributes #2, Jednotka: m3; Object Layer Attributes #2, Název_objektu: Stěna; Object Layer Attributes #2, Staticky nosná konstrukce: yes
ZDIVO Z CDm | Půdorys 4.NP | ZDIVO Z CDm 0.5 m |  | ZDIVO Z CDm | A | 1752HWa0798430615 | m3 | Celá stěna | Stávající | Zednické práce | ZDIVO Z CDm | yes | 1752Stě0798430617 | m3 | Stěna | 0 | 0.5 | 12.721 | 12.722 | 6.361 | 4.95 | 6.361 | 2.475 | 2.57
ZDIVO Z CDm | Půdorys 4.NP | EPS 0.1 m, ZDIVO Z CDm 0.5 m | 1 | ZDIVO Z CDm | A | 1752HWa0000000044 | m3 | Celá stěna | Stávající | Zateplovací systémy | EPS | no | 1752Stě0000000064 | m2 | Stěna | 0 | 0.6 | 2.256 | 2.256 | 1.254 | 0.8 | 1.254 | 0.48 | 2.82 | NEMSOK - Object Layer Attributes #2, 2D interakce: yes; Object Layer Attributes #2, Status: Stávající; Object Layer Attributes #2, Práce: Zednické práce; Object Layer Attributes #2, Materiál: ZDIVO Z CDm; Object Layer Attributes #2, Allright_Stavebni_dil_ID: 1752Stě0798430644; Object Layer Attributes #2, Jednotka: m3; Object Layer Attributes #2, Název_objektu: Stěna; Object Layer Attributes #2, Staticky nosná konstrukce: yes
ZDIVO Z CDm | Půdorys 4.NP | ZDIVO Z CDm 0.125 m |  | ZDIVO Z CDm | A | 1752HWa0798427753 | m3 | Celá stěna | Stávající | Zednické práce | ZDIVO Z CDm | yes | 1752Stě0798427754 | m3 | Stěna | 0 | 0.125 | 5.397 | 2.973 | 0.675 | 2.1 | 0.372 | 0.263 | 2.57
ZDIVO Z CDm | Půdorys 4.NP | EPS | 1 | ZDIVO Z CDm | A | 1752HWa0000004752 | m3 | Celá stěna | Stávající | Zateplovací systémy | EPS | no | 1752Stě0000004763 | m2 | Stěna | 0 | 0.6 | 18.33 | 12.57 | 10.057 | 6.45 | 6.781 | 3.85 | 2.82 | NEMSOK - Object Layer Attributes #2, 2D interakce: yes; Object Layer Attributes #2, Status: Stávající; Object Layer Attributes #2, Práce: Zednické práce; Object Layer Attributes #2, Materiál: ZDIVO Z CDm; Object Layer Attributes #2, Allright_Stavebni_dil_ID: 1752Stě0798430795; Object Layer Attributes #2, Jednotka: m3; Object Layer Attributes #2, Název_objektu: Stěna; Object Layer Attributes #2, Staticky nosná konstrukce: yes
ZDIVO Z CDm | Půdorys 4.NP | EPS 0.1 m, ZDIVO Z CDm 0.5 m |  | ZDIVO Z CDm | A | 1752HWa0000000004 | m3 | Celá stěna | Stávající | Zateplovací systémy | EPS | no | 1752Stě0000000033 | m2 | Stěna | 0 | 0.6 | 26.367 | 26.367 | 13.366 | 8.85 | 13.366 | 5.11 | 2.82 | NEMSOK - Object Layer Attributes #2, 2D interakce: yes; Object Layer Attributes #2, Status: Stávající; Object Layer Attributes #2, Práce: Zednické práce; Object Layer Attributes #2, Materiál: ZDIVO Z CDm; Object Layer Attributes #2, Allright_Stavebni_dil_ID: 1752Stě0798431139; Object Layer Attributes #2, Jednotka: m3; Object Layer Attributes #2, Název_objektu: Stěna; Object Layer Attributes #2, Staticky nosná konstrukce: yes
ZDIVO Z CDm | Půdorys 4.NP | ZDIVO Z CDm 0.3 m |  | ZDIVO Z CDm | A | 1752HWa0798428001 | m3 | Celá stěna | Stávající | Zednické práce | ZDIVO Z CDm | no | 1752Stě0798428009 | m3 | Stěna | 0 | 0.3 | 4.037 | 1.319 | 1.211 | 2.375 | 0.345 | 0.712 | 1.7
ZDIVO Z CDm | Půdorys 4.NP | ZDIVO Z CDm 0.125 m |  | ZDIVO Z CDm | A | 1752HWa0798431227 | m3 | Celá stěna | Stávající | Zednické práce | ZDIVO Z CDm | no | 1752Stě0798431228 | m3 | Stěna | 0 | 0.125 | 0.29 | 0.29 | 0.036 | 0.2 | 0.036 | 0.025 | 1.45
ZDIVO Z CDm | Půdorys 4.NP | ZDIVO Z CDm 0.125 m | 1 | ZDIVO Z CDm | A | 1752HWa0798431512 | m3 | Celá stěna | Stávající | Zednické práce | ZDIVO Z CDm | yes | 1752Stě0798431513 | m3 | Stěna | 0 | 0.125 | 2.516 | 2.516 | 0.315 | 0.825 | 0.315 | 0.103 | 3.05
ZDIVO Z CDm | Půdorys 4.NP | ZDIVO Z CDm 0.125 m | 1 | ZDIVO Z CDm | A | 1752HWa0798431524 | m3 | Celá stěna | Stávající | Zednické práce | ZDIVO Z CDm | yes | 1752Stě0798431525 | m3 | Stěna | 0 | 0.125 | 2.898 | 2.898 | 0.362 | 0.95 | 0.362 | 0.119 | 3.05
PÓROBETONOVÉ ZDIVO | Půdorys 4.NP | PÓROBETONOVÉ ZDIVO 0.08 m | 1 | PÓROBETONOVÉ ZDIVO | EI 120 | 1752HWa0798431571 | m3 | Celá stěna | Stávající | Zednické práce | PÓROBETONOVÉ ZDIVO |  | 1752Stě0798431572 | m2 | Stěna | 1.111 | 0.08 | 16.089 | 16.089 | 1.287 | 5.275 | 1.287 | 0.422 | 3.05 | Pset_WallCommon - AcousticRating: 37 dB
ZDIVO Z CDm | Půdorys 4.NP | ZDIVO Z CDm 0.125 m | 1 | ZDIVO Z CDm | A | 1752HWa0798431605 | m3 | Celá stěna | Stávající | Zednické práce | ZDIVO Z CDm | yes | 1752Stě0798431606 | m3 | Stěna | 0 | 0.125 | 2.913 | 2.913 | 0.364 | 0.955 | 0.364 | 0.119 | 3.05
ZDIVO Z CDm | Půdorys 4.NP | ZDIVO Z CDm 0.125 m | 1 | ZDIVO Z CDm | A | 1752HWa0798431614 | m3 | Celá stěna | Stávající | Zednické práce | ZDIVO Z CDm | yes | 1752Stě0798431615 | m3 | Stěna | 0 | 0.125 | 0.976 | 0.976 | 0.122 | 0.32 | 0.122 | 0.04 | 3.05
ZDIVO Z CDm | Půdorys 4.NP | ZDIVO Z CDm 0.125 m | 1 | ZDIVO Z CDm | A | 1752HWa0798431648 | m3 | Celá stěna | Stávající | Zednické práce | ZDIVO Z CDm | yes | 1752Stě0798431653 | m3 | Stěna | 0 | 0.125 | 1.906 | 1.906 | 0.238 | 0.625 | 0.238 | 0.078 | 3.05
ZELEZOBETONOVÁ KCE | Půdorys 4.NP | ZELEZOBETONOVÁ KCE 0.32 m | 1 | ZELEZOBETONOVÁ KCE | A | 1752HWa0000009499 | m3 | Celá stěna | Stávající | Betonářské práce | ZELEZOBETONOVÁ KCE |  | 1752Stě0000010545 | m3 | Stěna | 0 | 0.32 | 106.776 | 73.44 | 34.168 | 32.356 | 22.899 | 10.354 | 3.3
ZDIVO Z CDm | Půdorys 4.NP | ZDIVO Z CDm 0.125 m | 1 | ZDIVO Z CDm | A | 1752HWa0798431650 | m3 | Celá stěna | Stávající | Zednické práce | ZDIVO Z CDm | yes | 1752Stě0798431652 | m3 | Stěna | 0 | 0.125 | 0.839 | 0.839 | 0.105 | 0.275 | 0.105 | 0.034 | 3.05
PÓROBETONOVÉ ZDIVO | Půdorys 4.NP | PÓROBETONOVÉ ZDIVO 0.08 m | 1 | PÓROBETONOVÉ ZDIVO | EI 120 | 1752HWa0798431643 | m3 | Celá stěna | Stávající | Zednické práce | PÓROBETONOVÉ ZDIVO |  | 1752Stě0798431651 | m2 | Stěna | 1.111 | 0.08 | 4.712 | 4.712 | 0.377 | 1.545 | 0.377 | 0.124 | 3.05 | Pset_WallCommon - AcousticRating: 37 dB
PÓROBETONOVÉ ZDIVO | Půdorys 4.NP | PÓROBETONOVÉ ZDIVO 0.08 m | 1 | PÓROBETONOVÉ ZDIVO | EI 120 | 1752HWa0798431645 | m3 | Celá stěna | Stávající | Zednické práce | PÓROBETONOVÉ ZDIVO |  | 1752Stě0798431646 | m2 | Stěna | 1.111 | 0.08 | 7.625 | 7.625 | 0.61 | 2.5 | 0.61 | 0.2 | 3.05 | Pset_WallCommon - AcousticRating: 37 dB
PÓROBETONOVÉ ZDIVO | Půdorys 4.NP | PÓROBETONOVÉ ZDIVO 0.08 m | 1 | PÓROBETONOVÉ ZDIVO | EI 120 | 1752HWa0798431587 | m3 | Celá stěna | Stávající | Zednické práce | PÓROBETONOVÉ ZDIVO |  | 1752Stě0798431588 | m2 | Stěna | 1.111 | 0.08 | 6.618 | 6.619 | 0.529 | 2.17 | 0.529 | 0.174 | 3.05 | Pset_WallCommon - AcousticRating: 37 dB
PÓROBETONOVÉ ZDIVO | Půdorys 4.NP | PÓROBETONOVÉ ZDIVO 0.08 m | 1 | PÓROBETONOVÉ ZDIVO | EI 120 | 1752HWa0798431594 | m3 | Celá stěna | Stávající | Zednické práce | PÓROBETONOVÉ ZDIVO |  | 1752Stě0798431595 | m2 | Stěna | 1.111 | 0.08 | 7.625 | 7.625 | 0.61 | 2.5 | 0.61 | 0.2 | 3.05 | Pset_WallCommon - AcousticRating: 37 dB
ZDIVO Z CDm | Půdorys 4.NP | ZDIVO Z CDm 0.125 m | 1 | ZDIVO Z CDm | A | 1752HWa0798431865 | m3 | Celá stěna | Stávající | Zednické práce | ZDIVO Z CDm | yes | 1752Stě0798431866 | m3 | Stěna | 0 | 0.125 | 7.625 | 7.625 | 0.953 | 2.5 | 0.953 | 0.312 | 3.05
ZDIVO Z CDm | Půdorys 4.NP | ZDIVO Z CDm 0.125 m | 1 | ZDIVO Z CDm | A | 1752HWa0798431918 | m3 | Celá stěna | Stávající | Zednické práce | ZDIVO Z CDm | yes | 1752Stě0798431919 | m3 | Stěna | 0 | 0.125 | 1.906 | 1.906 | 0.238 | 0.625 | 0.238 | 0.078 | 3.05
ZDIVO Z CDm | Půdorys 4.NP | ZDIVO Z CDm 0.125 m | 1 | ZDIVO Z CDm | A | 1752HWa0798431944 | m3 | Celá stěna | Stávající | Zednické práce | ZDIVO Z CDm | yes | 1752Stě0798431945 | m3 | Stěna | 0 | 0.125 | 0.839 | 0.839 | 0.105 | 0.275 | 0.105 | 0.034 | 3.05
ZDIVO Z CDm | Půdorys 4.NP | ZDIVO Z CDm 0.125 m | 1 | ZDIVO Z CDm | A | 1752HWa0798431990 | m3 | Celá stěna | Stávající | Zednické práce | ZDIVO Z CDm | yes | 1752Stě0798431991 | m3 | Stěna | 0 | 0.125 | 6.619 | 6.619 | 0.827 | 2.17 | 0.827 | 0.271 | 3.05
ZDIVO Z CDm | Půdorys 4.NP | ZDIVO Z CDm 0.125 m | 1 | ZDIVO Z CDm | A | 1752HWa0798432001 | m3 | Celá stěna | Stávající | Zednické práce | ZDIVO Z CDm | yes | 1752Stě0798432002 | m3 | Stěna | 0 | 0.125 | 2.913 | 2.913 | 0.364 | 0.955 | 0.364 | 0.119 | 3.05
ZDIVO Z CDm | Půdorys 4.NP | ZDIVO Z CDm 0.125 m | 1 | ZDIVO Z CDm | A | 1752HWa0798432010 | m3 | Celá stěna | Stávající | Zednické práce | ZDIVO Z CDm | yes | 1752Stě0798432011 | m3 | Stěna | 0 | 0.125 | 0.839 | 0.839 | 0.105 | 0.275 | 0.105 | 0.034 | 3.05
PÓROBETONOVÉ ZDIVO | Půdorys 4.NP | PÓROBETONOVÉ ZDIVO 0.08 m | 1 | PÓROBETONOVÉ ZDIVO | EI 120 | 1752HWa0798432027 | m3 | Celá stěna | Stávající | Zednické práce | PÓROBETONOVÉ ZDIVO |  | 1752Stě0798432028 | m2 | Stěna | 1.111 | 0.08 | 4.712 | 4.712 | 0.377 | 1.545 | 0.377 | 0.124 | 3.05 | Pset_WallCommon - AcousticRating: 37 dB
EPS | Půdorys 4.NP | EPS 0.1 m |  | EPS |  | 1754HWa0000000850 | m3 | Celá stěna | Stávající | Zateplovací systémy | EPS | no | 1754Stě0000000948 | m2 | Stěna |  | 0.1 | 0.55 | 0.55 | 0.055 | 2.2 | 0.055 | 0.22 | 0.25
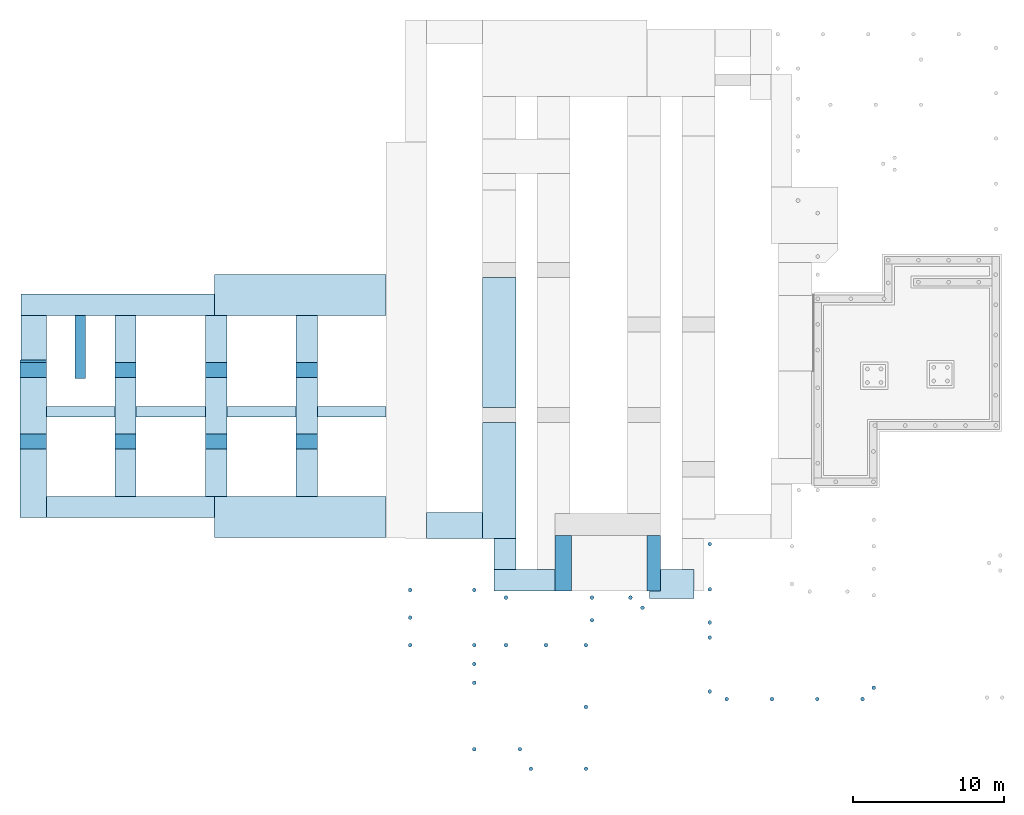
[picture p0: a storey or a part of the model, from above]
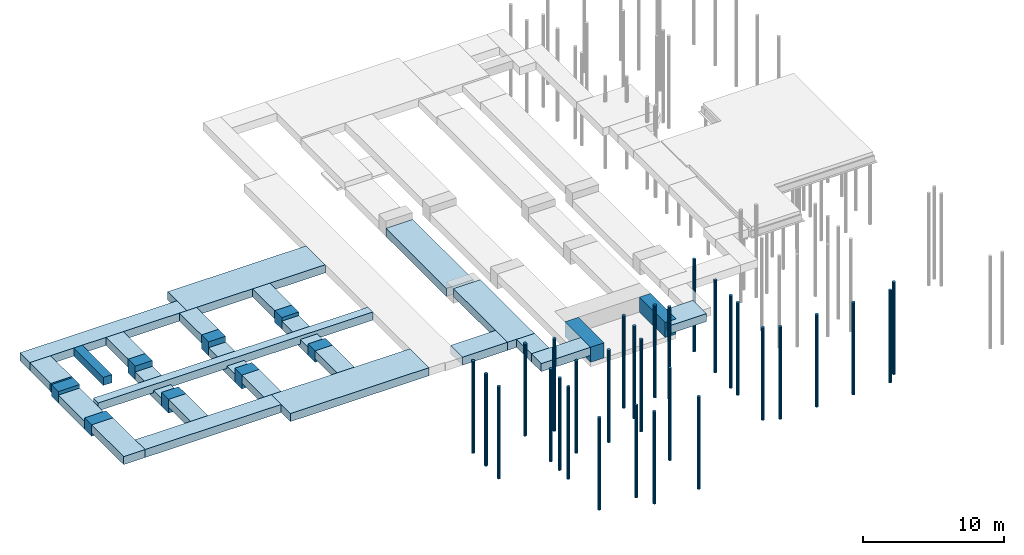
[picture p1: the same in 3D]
Properties of the parts of a building model (IFC4), part 41 of 45

# IfcWall (2385)
Name | In | Material | Faktor | Označení | Požární odolnost | Allright_Stavebni_dil_ID | Jednotka | Název_objektu | Object Layer Attributes #1, Status | Object Layer Attributes #1, Práce | Object Layer Attributes #1, Materiál | Object Layer Attributes #1, Staticky nosná konstrukce | Object Layer Attributes #1, Allright_Stavebni_dil_ID | Object Layer Attributes #1, Jednotka | Object Layer Attributes #1, Název_objektu | ThermalTransmittance (W/K/m2) | Width (m) | GrossSideArea (m2) | NetSideArea (m2) | GrossVolume (m3) | Length (m) | NetVolume (m3) | GrossFootprintArea (m2) | Height (m)
EPS | Půdorys 4.NP | EPS 0.1 m |  | EPS |  | 1754HWa0000000852 | m3 | Celá stěna | Stávající | Zateplovací systémy | EPS | no | 1754Stě0000000946 | m2 | Stěna |  | 0.1 | 1.15 | 1.15 | 0.115 | 4.6 | 0.115 | 0.46 | 0.25
EPS | Půdorys 4.NP | EPS 0.1 m |  | EPS |  | 1754HWa0000000853 | m3 | Celá stěna | Stávající | Zateplovací systémy | EPS | no | 1754Stě0000000942 | m2 | Stěna |  | 0.1 | 1.15 | 1.15 | 0.115 | 4.6 | 0.115 | 0.46 | 0.25
 | Půdorys 4.NP | ZELEZOBETONOVÁ KCE 0.5 m |  |  |  | 1754HWa0000000030 | m3 | Celá stěna | Stávající | Betonářské práce | ZELEZOBETONOVÁ KCE | yes | 1754Ven0000000045 | m2 | Věnec |  | 0.5 | 1.888 | 1.888 | 0.944 | 0 | 0.944 | 3.775 | 0.25
 | Půdorys 4.NP | ZELEZOBETONOVÁ KCE 0.5 m |  |  |  | 1754HWa0000000034 | m3 | Celá stěna | Stávající | Betonářské práce | ZELEZOBETONOVÁ KCE | yes | 1754Ven0000000043 | m2 | Věnec |  | 0.5 | 1.888 | 1.888 | 0.944 | 0 | 0.944 | 3.775 | 0.25
 | Půdorys 4.NP | ZELEZOBETONOVÁ KCE 0.5 m |  |  |  | 1754HWa0000000032 | m3 | Celá stěna | Stávající | Betonářské práce | ZELEZOBETONOVÁ KCE | yes | 1754Ven0000000041 | m2 | Věnec |  | 0.5 | 0.75 | 0.75 | 0.375 | 0 | 0.375 | 1.5 | 0.25
 | Půdorys 4.NP | ZELEZOBETONOVÁ KCE 0.45 m, LIGNOPOR 0.05 m |  |  |  | 1754HWa0000000004 | m3 | Celá stěna | Stávající | Betonářské práce | ZELEZOBETONOVÁ KCE | yes | 1754Ven0000000051 | m2 | Věnec |  | 0.5 | 2.325 | 2.325 | 1.106 | 0 | 1.106 | 4.425 | 0.25 | NEMSOK - Object Layer Attributes #2, 2D interakce: yes; Object Layer Attributes #2, Status: Stávající; Object Layer Attributes #2, Práce: Zateplovací systémy; Object Layer Attributes #2, Materiál: LIGNOPOR; Object Layer Attributes #2, Allright_Stavebni_dil_ID: 1754Ven0000000015; Object Layer Attributes #2, Jednotka: m2; Object Layer Attributes #2, Název_objektu: Věnec; Object Layer Attributes #2, Staticky nosná konstrukce: no
 | Půdorys 4.NP | ZELEZOBETONOVÁ KCE 0.45 m, LIGNOPOR 0.05 m |  |  |  | 1754HWa0000000006 | m3 | Celá stěna | Stávající | Betonářské práce | ZELEZOBETONOVÁ KCE | yes | 1754Ven0000000027 | m2 | Věnec |  | 0.5 | 0.837 | 0.838 | 0.362 | 0 | 0.362 | 1.45 | 0.25 | NEMSOK - Object Layer Attributes #2, 2D interakce: yes; Object Layer Attributes #2, Status: Stávající; Object Layer Attributes #2, Práce: Zateplovací systémy; Object Layer Attributes #2, Materiál: LIGNOPOR; Object Layer Attributes #2, Allright_Stavebni_dil_ID: 1754Ven0000000025; Object Layer Attributes #2, Jednotka: m2; Object Layer Attributes #2, Název_objektu: Věnec; Object Layer Attributes #2, Staticky nosná konstrukce: no
 | Půdorys 4.NP | ZELEZOBETONOVÁ KCE 0.45 m, LIGNOPOR 0.05 m |  |  |  | 1754HWa0000000008 | m3 | Celá stěna | Stávající | Betonářské práce | ZELEZOBETONOVÁ KCE | yes | 1754Ven0000000023 | m2 | Věnec |  | 0.5 | 0.188 | 0.188 | 0.049 | 0 | 0.049 | 0.195 | 0.25 | NEMSOK - Object Layer Attributes #2, 2D interakce: yes; Object Layer Attributes #2, Status: Stávající; Object Layer Attributes #2, Práce: Zateplovací systémy; Object Layer Attributes #2, Materiál: LIGNOPOR; Object Layer Attributes #2, Allright_Stavebni_dil_ID: 1754Ven0000000021; Object Layer Attributes #2, Jednotka: m2; Object Layer Attributes #2, Název_objektu: Věnec; Object Layer Attributes #2, Staticky nosná konstrukce: no
 | Půdorys 4.NP | ZELEZOBETONOVÁ KCE 0.45 m, LIGNOPOR 0.05 m |  |  |  | 1754HWa0000000009 | m3 | Celá stěna | Stávající | Betonářské práce | ZELEZOBETONOVÁ KCE | yes | 1754Ven0000000039 | m2 | Věnec |  | 0.5 | 0.875 | 0.875 | 0.432 | 0 | 0.432 | 1.727 | 0.25 | NEMSOK - Object Layer Attributes #2, 2D interakce: yes; Object Layer Attributes #2, Status: Stávající; Object Layer Attributes #2, Práce: Zateplovací systémy; Object Layer Attributes #2, Materiál: LIGNOPOR; Object Layer Attributes #2, Allright_Stavebni_dil_ID: 1754Ven0000000017; Object Layer Attributes #2, Jednotka: m2; Object Layer Attributes #2, Název_objektu: Věnec; Object Layer Attributes #2, Staticky nosná konstrukce: no
 | Půdorys 4.NP | ZELEZOBETONOVÁ KCE 0.45 m, LIGNOPOR 0.05 m |  |  |  | 1754HWa0000000540 | m3 | Celá stěna | Stávající | Betonářské práce | ZELEZOBETONOVÁ KCE | yes | 1754Ven0000000541 | m2 | Věnec |  | 0.5 | 1.012 | 1.013 | 0.456 | 0 | 0.456 | 1.822 | 0.25 | NEMSOK - Object Layer Attributes #2, 2D interakce: yes; Object Layer Attributes #2, Status: Stávající; Object Layer Attributes #2, Práce: Zateplovací systémy; Object Layer Attributes #2, Materiál: LIGNOPOR; Object Layer Attributes #2, Allright_Stavebni_dil_ID: 1754Ven0000000542; Object Layer Attributes #2, Jednotka: m2; Object Layer Attributes #2, Název_objektu: Věnec; Object Layer Attributes #2, Staticky nosná konstrukce: no
 | Půdorys 4.NP | ZELEZOBETONOVÁ KCE 0.45 m, LIGNOPOR 0.05 m |  |  |  | 1754HWa0000000002 | m3 | Celá stěna | Stávající | Betonářské práce | ZELEZOBETONOVÁ KCE | yes | 1754Ven0000000047 | m2 | Věnec |  | 0.5 | 2.138 | 2.138 | 1.058 | 0 | 1.058 | 4.23 | 0.25 | NEMSOK - Object Layer Attributes #2, 2D interakce: yes; Object Layer Attributes #2, Status: Stávající; Object Layer Attributes #2, Práce: Zateplovací systémy; Object Layer Attributes #2, Materiál: LIGNOPOR; Object Layer Attributes #2, Allright_Stavebni_dil_ID: 1754Ven0000000029; Object Layer Attributes #2, Jednotka: m2; Object Layer Attributes #2, Název_objektu: Věnec; Object Layer Attributes #2, Staticky nosná konstrukce: no
 | Půdorys 4.NP | ZELEZOBETONOVÁ KCE 0.45 m, LIGNOPOR 0.05 m |  |  |  | 1754HWa0000000366 | m3 | Celá stěna | Stávající | Betonářské práce | ZELEZOBETONOVÁ KCE | yes | 1754Ven0000000367 | m2 | Věnec |  | 0.5 | 1.012 | 1.013 | 0.456 | 0 | 0.456 | 1.822 | 0.25 | NEMSOK - Object Layer Attributes #2, 2D interakce: yes; Object Layer Attributes #2, Status: Stávající; Object Layer Attributes #2, Práce: Zateplovací systémy; Object Layer Attributes #2, Materiál: LIGNOPOR; Object Layer Attributes #2, Allright_Stavebni_dil_ID: 1754Ven0000000368; Object Layer Attributes #2, Jednotka: m2; Object Layer Attributes #2, Název_objektu: Věnec; Object Layer Attributes #2, Staticky nosná konstrukce: no
 | Půdorys 4.NP | ZELEZOBETONOVÁ KCE 0.45 m, LIGNOPOR 0.05 m |  |  |  | 1754HWa0000000003 | m3 | Celá stěna | Stávající | Betonářské práce | ZELEZOBETONOVÁ KCE | yes | 1754Ven0000000049 | m2 | Věnec |  | 0.5 | 1.6 | 1.6 | 0.794 | 0 | 0.794 | 3.178 | 0.25 | NEMSOK - Object Layer Attributes #2, 2D interakce: yes; Object Layer Attributes #2, Status: Stávající; Object Layer Attributes #2, Práce: Zateplovací systémy; Object Layer Attributes #2, Materiál: LIGNOPOR; Object Layer Attributes #2, Allright_Stavebni_dil_ID: 1754Ven0000000019; Object Layer Attributes #2, Jednotka: m2; Object Layer Attributes #2, Název_objektu: Věnec; Object Layer Attributes #2, Staticky nosná konstrukce: no
ZDIVO Z CDm | Půdorys 5.NP | ZDIVO Z CDm 0.5 m |  | ZDIVO Z CDm | A | 1852HWa0000006267 | m3 | Celá stěna | Stávající | Zednické práce | ZDIVO Z CDm | yes | 1852Stě0000006268 | m3 | Stěna | 0 | 0.5 | 0.962 | 0.962 | 0.481 | 2.6 | 0.481 | 1.3 | 0.37
ZDIVO Z CDm | Půdorys 5.NP | ZDIVO Z CDm 0.5 m |  | ZDIVO Z CDm | A | 1852HWa0000000009 | m3 | Celá stěna | Stávající | Zednické práce | ZDIVO Z CDm | yes | 1852Stě0000001382 | m3 | Stěna | 0 | 0.5 | 23.708 | 23.708 | 11.854 | 5.45 | 11.854 | 2.725 | 4.35
ZDIVO Z CDm | Půdorys 5.NP | ZDIVO Z CDm 0.5 m |  | ZDIVO Z CDm | A | 1852HWa0000000011 | m3 | Celá stěna | Stávající | Zednické práce | ZDIVO Z CDm | yes | 1852Stě0000001376 | m3 | Stěna | 0 | 0.5 | 15.225 | 15.225 | 7.613 | 3.5 | 7.613 | 1.75 | 4.35
PLYNOSILIKÁT | Půdorys 5.NP | PLYNOSILIKÁT 0.3 m | 1 | PLYNOSILIKÁT | REI 180 | 1852HWa0000010517 | m3 | Celá stěna | Stávající | Zednické práce | PLYNOSILIKÁT |  | 1852Stě0000010518 | m3 | Stěna | 0.541 | 0.3 | 4 | 4 | 1.2 | 4 | 1.2 | 1.2 | 1 | Pset_WallCommon - AcousticRating: 48 dB
ZDIVO Z CDm | Půdorys 5.NP | ZDIVO Z CDm 0.2 m | 1 | ZDIVO Z CDm | A | 1852HWa0000010611 | m3 | Celá stěna | Stávající | Zednické práce | ZDIVO Z CDm | yes | 1852Stě0000010612 | m3 | Stěna | 0 | 0.2 | 3 | 3 | 0.6 | 3 | 0.6 | 0.6 | 1
ZDIVO Z CDm | Půdorys 5.NP | ZDIVO Z CDm 0.25 m | 1 | ZDIVO Z CDm | A | 1852HWa0000010573 | m3 | Celá stěna | Stávající | Zednické práce | ZDIVO Z CDm | yes | 1852Stě0000010574 | m3 | Stěna | 0 | 0.25 | 3.25 | 3.25 | 0.813 | 3.25 | 0.813 | 0.813 | 1
ZDIVO Z CDm | Půdorys 5.NP | ZDIVO Z CDm 0.25 m | 1 | ZDIVO Z CDm | A | 1852HWa0000010558 | m3 | Celá stěna | Stávající | Zednické práce | ZDIVO Z CDm | yes | 1852Stě0000010559 | m3 | Stěna | 0 | 0.25 | 8.35 | 8.35 | 2.087 | 8.35 | 2.087 | 2.087 | 1
ZDIVO Z CDm | Půdorys 5.NP | ZDIVO Z CDm 0.125 m | 1 | ZDIVO Z CDm | A | 1852HWa0000010714 | m3 | Celá stěna | Stávající | Zednické práce | ZDIVO Z CDm | yes | 1852Stě0000010723 | m3 | Stěna | 0 | 0.125 | 53.424 | 50.293 | 6.678 | 13.525 | 6.287 | 1.691 | 3.95
ZDIVO Z CDm | Půdorys 5.NP | ZDIVO Z CDm 0.125 m | 1 | ZDIVO Z CDm | A | 1852HWa0000011091 | m3 | Celá stěna | Stávající | Zednické práce | ZDIVO Z CDm | yes | 1852Stě0000011092 | m3 | Stěna | 0 | 0.125 | 7.406 | 5.588 | 0.926 | 1.875 | 0.699 | 0.234 | 3.95
ZDIVO Z CDm | Půdorys 5.NP | ZDIVO Z CDm 0.125 m | 1 | ZDIVO Z CDm | A | 1852HWa0000011103 | m3 | Celá stěna | Stávající | Zednické práce | ZDIVO Z CDm | yes | 1852Stě0000011104 | m3 | Stěna | 0 | 0.125 | 1.778 | 1.778 | 0.222 | 0.45 | 0.222 | 0.056 | 3.95
ZDIVO Z CDm | Půdorys 5.NP | ZDIVO Z CDm 0.125 m | 1 | ZDIVO Z CDm | A | 1852HWa0000011144 | m3 | Celá stěna | Stávající | Zednické práce | ZDIVO Z CDm | yes | 1852Stě0000011145 | m3 | Stěna | 0 | 0.125 | 1.284 | 1.284 | 0.16 | 0.325 | 0.16 | 0.041 | 3.95
ZDIVO Z CDm | Půdorys 5.NP | ZDIVO Z CDm 0.25 m | 1 | ZDIVO Z CDm | A | 1852HWa0000010590 | m3 | Celá stěna | Stávající | Zednické práce | ZDIVO Z CDm | yes | 1852Stě0000010591 | m3 | Stěna | 0 | 0.25 | 8.35 | 8.35 | 2.087 | 8.35 | 2.087 | 2.087 | 1
PLYNOSILIKÁT | Půdorys 5.NP | PLYNOSILIKÁT 0.3 m |  | PLYNOSILIKÁT | REI 180 | 1852HWa0000010482 | m3 | Celá stěna | Stávající | Zednické práce | PLYNOSILIKÁT |  | 1852Stě0000010484 | m3 | Stěna | 0.541 | 0.3 | 9.5 | 9.5 | 2.85 | 9.5 | 2.85 | 2.85 | 1 | Pset_WallCommon - AcousticRating: 48 dB
ZDIVO Z CDm | Půdorys 5.NP | ZDIVO Z CDm 0.4 m | 1 | ZDIVO Z CDm | A | 1852HWa0000010626 | m3 | Celá stěna | Stávající | Zednické práce | ZDIVO Z CDm | yes | 1852Stě0000010627 | m3 | Stěna | 0 | 0.4 | 3 | 3 | 1.2 | 3 | 1.2 | 1.2 | 1
ZDIVO Z CDm | Půdorys 5.NP | ZDIVO Z CDm 0.25 m | 1 | ZDIVO Z CDm | A | 1852HWa0000010543 | m3 | Celá stěna | Stávající | Zednické práce | ZDIVO Z CDm | yes | 1852Stě0000010544 | m3 | Stěna | 0 | 0.25 | 3.25 | 3.25 | 0.813 | 3.25 | 0.813 | 0.813 | 1
ZELEZOBETONOVÁ KCE | Půdorys 5.NP | ZELEZOBETONOVÁ KCE 0.2 m | 1 | ZELEZOBETONOVÁ KCE | A | 1852HWa0000010696 | m3 | Celá stěna | Stávající | Betonářské práce | ZELEZOBETONOVÁ KCE |  | 1852Stě0000010762 | m3 | Stěna | 0 | 0.2 | 5.925 | 5.925 | 1.185 | 1.5 | 1.185 | 0.3 | 3.95
ZELEZOBETONOVÁ KCE | Půdorys 5.NP | ZELEZOBETONOVÁ KCE 0.2 m |  | ZELEZOBETONOVÁ KCE | A | 1852HWa0000010694 | m3 | Celá stěna | Stávající | Betonářské práce | ZELEZOBETONOVÁ KCE | yes | 1852Stě0000010772 | m3 | Stěna | 0 | 0.2 | 18.96 | 18.96 | 3.792 | 4.8 | 3.792 | 0.96 | 3.95
ZELEZOBETONOVÁ KCE | Půdorys 5.NP | ZELEZOBETONOVÁ KCE 0.2 m | 1 | ZELEZOBETONOVÁ KCE | A | 1852HWa0000010690 | m3 | Celá stěna | Stávající | Betonářské práce | ZELEZOBETONOVÁ KCE |  | 1852Stě0000010774 | m3 | Stěna | 0 | 0.2 | 18.96 | 18.96 | 3.792 | 4.8 | 3.792 | 0.96 | 3.95
ZELEZOBETONOVÁ KCE | Půdorys 5.NP | ZELEZOBETONOVÁ KCE 0.2 m | 1 | ZELEZOBETONOVÁ KCE | A | 1852HWa0798427598 | m3 | Celá stěna | Stávající | Betonářské práce | ZELEZOBETONOVÁ KCE |  | 1852Stě0798427600 | m3 | Stěna | 0 | 0.2 | 18.96 | 18.96 | 3.792 | 4.8 | 3.792 | 0.96 | 3.95
ZDIVO Z CDm | Půdorys 5.NP | ZDIVO Z CDm 0.15 m |  | ZDIVO Z CDm | A | 1852HWa0798428740 | m3 | Celá stěna | Stávající | Zednické práce | ZDIVO Z CDm | no | 1852Stě0798428741 | m3 | Stěna | 0 | 0.15 | 0.428 | 0.428 | 0.064 | 0.45 | 0.064 | 0.068 | 0.95
ZDIVO Z CDm | Půdorys 5.NP | ZDIVO Z CDm 0.15 m |  | ZDIVO Z CDm | A | 1852HWa0798428750 | m3 | Celá stěna | Stávající | Zednické práce | ZDIVO Z CDm | no | 1852Stě0798428751 | m3 | Stěna | 0 | 0.15 | 0.428 | 0.428 | 0.064 | 0.45 | 0.064 | 0.068 | 0.95
ZDIVO Z CDm | Půdorys 5.NP | ZDIVO Z CDm 0.15 m |  | ZDIVO Z CDm | A | 1852HWa0798428762 | m3 | Celá stěna | Stávající | Zednické práce | ZDIVO Z CDm | no | 1852Stě0798428763 | m3 | Stěna | 0 | 0.15 | 0.285 | 0.285 | 0.043 | 0.3 | 0.043 | 0.045 | 0.95
ZDIVO Z CDm | Půdorys 5.NP | ZDIVO Z CDm 0.15 m |  | ZDIVO Z CDm | A | 1852HWa0798428735 | m3 | Celá stěna | Stávající | Zednické práce | ZDIVO Z CDm | no | 1852Stě0798428736 | m3 | Stěna | 0 | 0.15 | 0.57 | 0.57 | 0.086 | 0.6 | 0.086 | 0.09 | 0.95
ZDIVO Z CDm | Půdorys 5.NP | ZDIVO Z CDm 0.15 m |  | ZDIVO Z CDm | A | 1852HWa0798428812 | m3 | Celá stěna | Stávající | Zednické práce | ZDIVO Z CDm | no | 1852Stě0798428823 | m3 | Stěna | 0 | 0.15 | 0.428 | 0.428 | 0.064 | 0.45 | 0.064 | 0.068 | 0.95
ZDIVO Z CDm | Půdorys 5.NP | ZDIVO Z CDm 0.15 m |  | ZDIVO Z CDm | A | 1852HWa0798428814 | m3 | Celá stěna | Stávající | Zednické práce | ZDIVO Z CDm | no | 1852Stě0798428818 | m3 | Stěna | 0 | 0.15 | 0.428 | 0.428 | 0.064 | 0.45 | 0.064 | 0.068 | 0.95
ZDIVO Z CDm | Půdorys 5.NP | ZDIVO Z CDm 0.15 m |  | ZDIVO Z CDm | A | 1852HWa0798428816 | m3 | Celá stěna | Stávající | Zednické práce | ZDIVO Z CDm | no | 1852Stě0798428822 | m3 | Stěna | 0 | 0.15 | 0.285 | 0.285 | 0.043 | 0.3 | 0.043 | 0.045 | 0.95
ZDIVO Z CDm | Půdorys 5.NP | ZDIVO Z CDm 0.15 m |  | ZDIVO Z CDm | A | 1852HWa0798428819 | m3 | Celá stěna | Stávající | Zednické práce | ZDIVO Z CDm | no | 1852Stě0798428821 | m3 | Stěna | 0 | 0.15 | 0.57 | 0.57 | 0.086 | 0.6 | 0.086 | 0.09 | 0.95
ZDIVO Z CDm | Půdorys 5.NP | ZDIVO Z CDm 0.15 m | 1 | ZDIVO Z CDm | A | 1852HWa0798428832 | m3 | Celá stěna | Stávající | Zednické práce | ZDIVO Z CDm | no | 1852Stě0798428833 | m3 | Stěna | 0 | 0.15 | 0.998 | 0.998 | 0.15 | 1.05 | 0.15 | 0.158 | 0.95
ZDIVO Z CDm | Půdorys 5.NP | ZDIVO Z CDm 0.15 m |  | ZDIVO Z CDm | A | 1852HWa0798428976 | m3 | Celá stěna | Stávající | Zednické práce | ZDIVO Z CDm | no | 1852Stě0798428987 | m3 | Stěna | 0 | 0.15 | 0.428 | 0.428 | 0.064 | 0.45 | 0.064 | 0.068 | 0.95
ZDIVO Z CDm | Půdorys 5.NP | ZDIVO Z CDm 0.15 m |  | ZDIVO Z CDm | A | 1852HWa0798428978 | m3 | Celá stěna | Stávající | Zednické práce | ZDIVO Z CDm | no | 1852Stě0798428982 | m3 | Stěna | 0 | 0.15 | 0.428 | 0.399 | 0.064 | 0.45 | 0.06 | 0.068 | 0.95
ZDIVO Z CDm | Půdorys 5.NP | ZDIVO Z CDm 0.15 m |  | ZDIVO Z CDm | A | 1852HWa0798428980 | m3 | Celá stěna | Stávající | Zednické práce | ZDIVO Z CDm | no | 1852Stě0798428986 | m3 | Stěna | 0 | 0.15 | 0.285 | 0.285 | 0.043 | 0.3 | 0.034 | 0.045 | 0.95
ZDIVO Z CDm | Půdorys 5.NP | ZDIVO Z CDm 0.15 m |  | ZDIVO Z CDm | A | 1852HWa0798428983 | m3 | Celá stěna | Stávající | Zednické práce | ZDIVO Z CDm | no | 1852Stě0798428985 | m3 | Stěna | 0 | 0.15 | 0.57 | 0.541 | 0.086 | 0.6 | 0.081 | 0.09 | 0.95
ZDIVO Z CDm | Půdorys 5.NP | EPS 0.1 m, ZDIVO Z CDm 0.25 m |  | ZDIVO Z CDm | A | 1852HWa0798429043 | m3 | Celá stěna | Stávající | Zateplovací systémy | EPS |  | 1852Stě0798429046 | m2 | Stěna | 0 | 0.35 | 5.94 | 5.94 | 2.079 | 3.6 | 2.079 | 1.26 | 1.65 | NEMSOK - Object Layer Attributes #2, 2D interakce: yes; Object Layer Attributes #2, Status: Stávající; Object Layer Attributes #2, Práce: Zednické práce; Object Layer Attributes #2, Materiál: ZDIVO Z CDm; Object Layer Attributes #2, Allright_Stavebni_dil_ID: 1852Stě0798429414; Object Layer Attributes #2, Jednotka: m3; Object Layer Attributes #2, Název_objektu: Stěna
ZDIVO Z CDm | Půdorys 5.NP | EPS 0.1 m, ZDIVO Z CDm 0.25 m |  | ZDIVO Z CDm | A | 1852HWa0798429059 | m3 | Celá stěna | Stávající | Zateplovací systémy | EPS |  | 1852Stě0798429062 | m2 | Stěna | 0 | 0.35 | 6.37 | 6.37 | 2.168 | 2.55 | 2.168 | 0.885 | 2.45 | NEMSOK - Object Layer Attributes #2, 2D interakce: yes; Object Layer Attributes #2, Status: Stávající; Object Layer Attributes #2, Práce: Zednické práce; Object Layer Attributes #2, Materiál: ZDIVO Z CDm; Object Layer Attributes #2, Allright_Stavebni_dil_ID: 1852Stě0798429381; Object Layer Attributes #2, Jednotka: m3; Object Layer Attributes #2, Název_objektu: Stěna
ZDIVO Z CDm | Půdorys 5.NP | EPS 0.1 m, ZDIVO Z CDm 0.25 m |  | ZDIVO Z CDm | A | 1852HWa0798427191 | m3 | Celá stěna | Stávající | Zateplovací systémy | EPS |  | 1852Stě0798427192 | m2 | Stěna | 0 | 0.35 | 7.301 | 7.301 | 2.402 | 2.855 | 2.402 | 0.98 | 2.45 | NEMSOK - Object Layer Attributes #2, 2D interakce: yes; Object Layer Attributes #2, Status: Stávající; Object Layer Attributes #2, Práce: Zednické práce; Object Layer Attributes #2, Materiál: ZDIVO Z CDm; Object Layer Attributes #2, Allright_Stavebni_dil_ID: 1852Stě0798429463; Object Layer Attributes #2, Jednotka: m3; Object Layer Attributes #2, Název_objektu: Stěna
YTONG 375 | Půdorys 5.NP | NEOVĚŘENO 0.33 m |  | YTONG 375 | REI 180 | 1852HWa0798429279 | m3 | Celá stěna | Stávající |  | NEOVĚŘENO | no | 1852Stě0798429282 | m3 | Stěna | 0.442 | 0.33 | 3.751 | 3.751 | 1.238 | 1.21 | 1.238 | 0.399 | 3.1 | Pset_WallCommon - AcousticRating: 49 dB
YTONG 375 | Půdorys 5.NP | NEOVĚŘENO 0.33 m |  | YTONG 375 | REI 180 | 1852HWa0798429287 | m3 | Celá stěna | Stávající |  | NEOVĚŘENO | no | 1852Stě0798429289 | m3 | Stěna | 0.442 | 0.33 | 3.751 | 3.751 | 1.238 | 1.21 | 1.238 | 0.399 | 3.1 | Pset_WallCommon - AcousticRating: 49 dB
PLYNOSILIKÁT | Půdorys 5.NP | EPS 0.05 m, PLYNOSILIKÁT 0.3 m | 1 | PLYNOSILIKÁT | REI 180 | 1852HWa0000010955 | m3 | Celá stěna | Stávající | Zateplovací systémy | EPS | no | 1852Stě0000010956 | m2 | Stěna | 0.541 | 0.35 | 48.51 | 48.51 | 15.697 | 11.375 | 15.697 | 3.938 | 4.2 | NEMSOK - Object Layer Attributes #2, 2D interakce: yes; Object Layer Attributes #2, Status: Stávající; Object Layer Attributes #2, Práce: Zednické práce; Object Layer Attributes #2, Materiál: PLYNOSILIKÁT; Object Layer Attributes #2, Allright_Stavebni_dil_ID: 1852Stě0798430438; Object Layer Attributes #2, Jednotka: m3; Object Layer Attributes #2, Název_objektu: Stěna; Object Layer Attributes #2, Staticky nosná konstrukce: no; Pset_WallCommon - AcousticRating: 48 dB
PLYNOSILIKÁT | Půdorys 5.NP | EPS 0.05 m, PLYNOSILIKÁT 0.3 m | 1 | PLYNOSILIKÁT | REI 180 | 1852HWa0000010950 | m3 | Celá stěna | Stávající | Zateplovací systémy | EPS | no | 1852Stě0000010951 | m2 | Stěna | 0.541 | 0.35 | 68.67 | 65.43 | 22.394 | 16.175 | 21.26 | 5.618 | 4.2 | NEMSOK - Object Layer Attributes #2, 2D interakce: yes; Object Layer Attributes #2, Status: Stávající; Object Layer Attributes #2, Práce: Zednické práce; Object Layer Attributes #2, Materiál: PLYNOSILIKÁT; Object Layer Attributes #2, Allright_Stavebni_dil_ID: 1852Stě0798430504; Object Layer Attributes #2, Jednotka: m3; Object Layer Attributes #2, Název_objektu: Stěna; Object Layer Attributes #2, Staticky nosná konstrukce: no; Pset_WallCommon - AcousticRating: 48 dB
PLYNOSILIKÁT | Půdorys 5.NP | EPS 0.05 m, PLYNOSILIKÁT 0.3 m | 1 | PLYNOSILIKÁT | REI 180 | 1852HWa0000011030 | m3 | Celá stěna | Stávající | Zateplovací systémy | EPS | no | 1852Stě0000011031 | m2 | Stěna | 0.541 | 0.35 | 48.51 | 45.595 | 15.698 | 11.375 | 14.677 | 3.938 | 4.2 | NEMSOK - Object Layer Attributes #2, 2D interakce: yes; Object Layer Attributes #2, Status: Stávající; Object Layer Attributes #2, Práce: Zednické práce; Object Layer Attributes #2, Materiál: PLYNOSILIKÁT; Object Layer Attributes #2, Allright_Stavebni_dil_ID: 1852Stě0798430690; Object Layer Attributes #2, Jednotka: m3; Object Layer Attributes #2, Název_objektu: Stěna; Object Layer Attributes #2, Staticky nosná konstrukce: no; Pset_WallCommon - AcousticRating: 48 dB
PLYNOSILIKÁT | Půdorys 5.NP | EPS 0.05 m, PLYNOSILIKÁT 0.3 m | 1 | PLYNOSILIKÁT | REI 180 | 1852HWa0000011053 | m3 | Celá stěna | Stávající | Zateplovací systémy | EPS | no | 1852Stě0000011054 | m2 | Stěna | 0.541 | 0.35 | 4.83 | 4.83 | 1.604 | 1.15 | 1.604 | 0.403 | 4.2 | NEMSOK - Object Layer Attributes #2, 2D interakce: yes; Object Layer Attributes #2, Status: Stávající; Object Layer Attributes #2, Práce: Zednické práce; Object Layer Attributes #2, Materiál: PLYNOSILIKÁT; Object Layer Attributes #2, Allright_Stavebni_dil_ID: 1852Stě0798430878; Object Layer Attributes #2, Jednotka: m3; Object Layer Attributes #2, Název_objektu: Stěna; Object Layer Attributes #2, Staticky nosná konstrukce: no; Pset_WallCommon - AcousticRating: 48 dB
PLYNOSILIKÁT | Půdorys 5.NP | EPS 0.05 m, PLYNOSILIKÁT 0.3 m | 1 | PLYNOSILIKÁT | REI 180 | 1852HWa0000011041 | m3 | Celá stěna | Stávající | Zateplovací systémy | EPS | no | 1852Stě0000011042 | m2 | Stěna | 0.541 | 0.35 | 15.204 | 13.544 | 5.109 | 3.645 | 4.528 | 1.282 | 4.2 | NEMSOK - Object Layer Attributes #2, 2D interakce: yes; Object Layer Attributes #2, Status: Stávající; Object Layer Attributes #2, Práce: Zednické práce; Object Layer Attributes #2, Materiál: PLYNOSILIKÁT; Object Layer Attributes #2, Allright_Stavebni_dil_ID: 1852Stě0798431109; Object Layer Attributes #2, Jednotka: m3; Object Layer Attributes #2, Název_objektu: Stěna; Object Layer Attributes #2, Staticky nosná konstrukce: no; Pset_WallCommon - AcousticRating: 48 dB
PLYNOSILIKÁT | Půdorys 5.NP | EPS 0.1 m, PLYNOSILIKÁT 0.3 m | 1 | PLYNOSILIKÁT | REI 180 | 1852HWa0798431301 | m3 | Celá stěna | Stávající | Zateplovací systémy | EPS | no | 1852Stě0798431322 | m2 | Stěna | 0.541 | 0.4 | 15.036 | 15.036 | 5.627 | 3.53 | 5.627 | 1.402 | 4.2 | NEMSOK - Object Layer Attributes #2, 2D interakce: yes; Object Layer Attributes #2, Status: Stávající; Object Layer Attributes #2, Práce: Zednické práce; Object Layer Attributes #2, Materiál: PLYNOSILIKÁT; Object Layer Attributes #2, Allright_Stavebni_dil_ID: 1852Stě0798431321; Object Layer Attributes #2, Jednotka: m3; Object Layer Attributes #2, Název_objektu: Stěna; Object Layer Attributes #2, Staticky nosná konstrukce: no; Pset_WallCommon - AcousticRating: 48 dB
PLYNOSILIKÁT | Půdorys 5.NP | EPS 0.15 m, PLYNOSILIKÁT 0.5 m |  | PLYNOSILIKÁT | REI 180 | 1852HWa0798432706 | m3 | Celá stěna | Stávající | Zateplovací systémy | EPS | no | 1852Stě0798432723 | m2 | Stěna | 0.541 | 0.65 | 6.716 | 6.716 | 3.051 | 1.46 | 3.051 | 0.949 | 4.6 | NEMSOK - Object Layer Attributes #2, 2D interakce: yes; Object Layer Attributes #2, Status: Stávající; Object Layer Attributes #2, Práce: Zednické práce; Object Layer Attributes #2, Materiál: PLYNOSILIKÁT; Object Layer Attributes #2, Allright_Stavebni_dil_ID: 1852Stě0798432722; Object Layer Attributes #2, Jednotka: m3; Object Layer Attributes #2, Název_objektu: Stěna; Object Layer Attributes #2, Staticky nosná konstrukce: no; Pset_WallCommon - AcousticRating: 48 dB
PLYNOSILIKÁT | Půdorys 5.NP | EPS 0.1 m, PLYNOSILIKÁT 0.3 m |  | PLYNOSILIKÁT | REI 180 | 1852HWa0000010463 | m3 | Celá stěna | Stávající | Zateplovací systémy | EPS | no | 1852Stě0000010464 | m2 | Stěna | 0.541 | 0.4 | 7.2 | 7.2 | 2.497 | 1.65 | 2.497 | 0.63 | 4 | NEMSOK - Object Layer Attributes #2, 2D interakce: yes; Object Layer Attributes #2, Status: Stávající; Object Layer Attributes #2, Práce: Zednické práce; Object Layer Attributes #2, Materiál: PLYNOSILIKÁT; Object Layer Attributes #2, Allright_Stavebni_dil_ID: 1852Stě0798432785; Object Layer Attributes #2, Jednotka: m3; Object Layer Attributes #2, Název_objektu: Stěna; Object Layer Attributes #2, Staticky nosná konstrukce: no; Pset_WallCommon - AcousticRating: 48 dB
PLYNOSILIKÁT | Půdorys 5.NP | EPS 0.15 m, PLYNOSILIKÁT 0.3 m |  | PLYNOSILIKÁT | REI 180 | 1852HWa0798433054 | m3 | Celá stěna | Stávající | Zateplovací systémy | EPS | no | 1852Stě0798433063 | m2 | Stěna | 0.541 | 0.45 | 10.8 | 9.45 | 4.819 | 2.7 | 4.212 | 1.215 | 4 | NEMSOK - Object Layer Attributes #2, 2D interakce: yes; Object Layer Attributes #2, Status: Stávající; Object Layer Attributes #2, Práce: Zednické práce; Object Layer Attributes #2, Materiál: PLYNOSILIKÁT; Object Layer Attributes #2, Allright_Stavebni_dil_ID: 1852Stě0798433064; Object Layer Attributes #2, Jednotka: m3; Object Layer Attributes #2, Název_objektu: Stěna; Object Layer Attributes #2, Staticky nosná konstrukce: no; Pset_WallCommon - AcousticRating: 48 dB
PLYNOSILIKÁT | Půdorys 5.NP | EPS 0.15 m, PLYNOSILIKÁT 0.5 m |  | PLYNOSILIKÁT | REI 180 | 1852HWa0000010501 | m3 | Celá stěna | Stávající | Zateplovací systémy | EPS | no | 1852Stě0000010502 | m2 | Stěna | 0.541 | 0.65 | 27.2 | 25.04 | 13.6 | 6.8 | 12.196 | 4.42 | 4 | NEMSOK - Object Layer Attributes #2, 2D interakce: yes; Object Layer Attributes #2, Status: Stávající; Object Layer Attributes #2, Práce: Zednické práce; Object Layer Attributes #2, Materiál: PLYNOSILIKÁT; Object Layer Attributes #2, Allright_Stavebni_dil_ID: 1852Stě0798431410; Object Layer Attributes #2, Jednotka: m3; Object Layer Attributes #2, Název_objektu: Stěna; Object Layer Attributes #2, Staticky nosná konstrukce: no; Pset_WallCommon - AcousticRating: 48 dB
PLYNOSILIKÁT | Půdorys 5.NP | EPS 0.1 m, PLYNOSILIKÁT 0.5 m |  | PLYNOSILIKÁT | REI 180 | 1852HWa0798432238 | m3 | Celá stěna | Stávající | Zateplovací systémy | EPS | no | 1852Stě0798432252 | m2 | Stěna | 0.541 | 0.6 | 6.164 | 6.164 | 2.352 | 1.29 | 2.352 | 0.754 | 4.6 | NEMSOK - Object Layer Attributes #2, 2D interakce: yes; Object Layer Attributes #2, Status: Stávající; Object Layer Attributes #2, Práce: Zednické práce; Object Layer Attributes #2, Materiál: PLYNOSILIKÁT; Object Layer Attributes #2, Allright_Stavebni_dil_ID: 1852Stě0798432253; Object Layer Attributes #2, Jednotka: m3; Object Layer Attributes #2, Název_objektu: Stěna; Object Layer Attributes #2, Staticky nosná konstrukce: no; Pset_WallCommon - AcousticRating: 48 dB
PLYNOSILIKÁT | Půdorys 5.NP | EPS 0.1 m, PLYNOSILIKÁT 0.3 m |  | PLYNOSILIKÁT | REI 180 | 1852HWa0798431020 | m3 | Celá stěna | Stávající | Zateplovací systémy | EPS | no | 1852Stě0798431026 | m2 | Stěna | 0.541 | 0.4 | 14.616 | 14.316 | 3.965 | 3.23 | 3.845 | 1.242 | 4.2 | NEMSOK - Object Layer Attributes #2, 2D interakce: yes; Object Layer Attributes #2, Status: Stávající; Object Layer Attributes #2, Práce: Zednické práce; Object Layer Attributes #2, Materiál: PLYNOSILIKÁT; Object Layer Attributes #2, Allright_Stavebni_dil_ID: 1852Stě0798431025; Object Layer Attributes #2, Jednotka: m3; Object Layer Attributes #2, Název_objektu: Stěna; Object Layer Attributes #2, Staticky nosná konstrukce: no; Pset_WallCommon - AcousticRating: 48 dB
PLYNOSILIKÁT | Půdorys 5.NP | EPS 0.05 m, PLYNOSILIKÁT 0.3 m |  | PLYNOSILIKÁT | REI 180 | 1852HWa0000010528 | m3 | Celá stěna | Stávající | Zateplovací systémy | EPS | no | 1852Stě0000010529 | m2 | Stěna | 0.541 | 0.35 | 3.444 | 3.444 | 0.861 | 0.82 | 0.861 | 0.287 | 4.2 | NEMSOK - Object Layer Attributes #2, 2D interakce: yes; Object Layer Attributes #2, Status: Stávající; Object Layer Attributes #2, Práce: Zednické práce; Object Layer Attributes #2, Materiál: PLYNOSILIKÁT; Object Layer Attributes #2, Allright_Stavebni_dil_ID: 1852Stě0798430123; Object Layer Attributes #2, Jednotka: m3; Object Layer Attributes #2, Název_objektu: Stěna; Object Layer Attributes #2, Staticky nosná konstrukce: no; Pset_WallCommon - AcousticRating: 48 dB
PLYNOSILIKÁT | Půdorys 5.NP | EPS 0.05 m, PLYNOSILIKÁT 0.3 m |  | PLYNOSILIKÁT | REI 180 | 1852HWa0000010468 | m3 | Celá stěna | Stávající | Zateplovací systémy | EPS | no | 1852Stě0000010469 | m2 | Stěna | 0.541 | 0.35 | 11.97 | 12.443 | 4.173 | 2.933 | 4.173 | 1.048 | 4.2 | NEMSOK - Object Layer Attributes #2, 2D interakce: yes; Object Layer Attributes #2, Status: Stávající; Object Layer Attributes #2, Práce: Zednické práce; Object Layer Attributes #2, Materiál: PLYNOSILIKÁT; Object Layer Attributes #2, Allright_Stavebni_dil_ID: 1852Stě0798430337; Object Layer Attributes #2, Jednotka: m3; Object Layer Attributes #2, Název_objektu: Stěna; Object Layer Attributes #2, Staticky nosná konstrukce: no; Pset_WallCommon - AcousticRating: 48 dB
PLYNOSILIKÁT | Půdorys 5.NP | EPS 0.05 m, PLYNOSILIKÁT 0.3 m |  | PLYNOSILIKÁT | REI 180 | 1852HWa0000010966 | m3 | Celá stěna | Stávající | Zateplovací systémy | EPS | no | 1852Stě0000010967 | m2 | Stěna | 0.541 | 0.35 | 4.83 | 4.83 | 1.604 | 1.15 | 1.604 | 0.402 | 4.2 | NEMSOK - Object Layer Attributes #2, 2D interakce: yes; Object Layer Attributes #2, Status: Stávající; Object Layer Attributes #2, Práce: Zednické práce; Object Layer Attributes #2, Materiál: PLYNOSILIKÁT; Object Layer Attributes #2, Allright_Stavebni_dil_ID: 1852Stě0798430392; Object Layer Attributes #2, Jednotka: m3; Object Layer Attributes #2, Název_objektu: Stěna; Object Layer Attributes #2, Staticky nosná konstrukce: no; Pset_WallCommon - AcousticRating: 48 dB
ZDIVO Z CDm | Půdorys 5.NP | EPS 0.1 m, ZDIVO Z CDm 0.5 m |  | ZDIVO Z CDm | A | 1852HWa0000000004 | m3 | Celá stěna | Stávající | Zateplovací systémy | EPS | no | 1852Stě0000001507 | m2 | Stěna | 0 | 0.6 | 43.47 | 43.47 | 23.596 | 9.15 | 23.596 | 5.37 | 4.6 | NEMSOK - Object Layer Attributes #2, 2D interakce: yes; Object Layer Attributes #2, Status: Stávající; Object Layer Attributes #2, Práce: Zednické práce; Object Layer Attributes #2, Materiál: ZDIVO Z CDm; Object Layer Attributes #2, Allright_Stavebni_dil_ID: 1852Stě0798433554; Object Layer Attributes #2, Jednotka: m3; Object Layer Attributes #2, Název_objektu: Stěna; Object Layer Attributes #2, Staticky nosná konstrukce: yes
ZDIVO Z CDm | Půdorys 5.NP | EPS | 1 | ZDIVO Z CDm | A | 1852HWa0000006100 | m3 | Celá stěna | Stávající | Zateplovací systémy | EPS | no | 1852Stě0000006107 | m2 | Stěna | 0 | 0.6 | 31.74 | 19.91 | 16.006 | 6.4 | 10.084 | 3.64 | 4.6 | NEMSOK - Object Layer Attributes #2, 2D interakce: yes; Object Layer Attributes #2, Status: Stávající; Object Layer Attributes #2, Práce: Zednické práce; Object Layer Attributes #2, Materiál: ZDIVO Z CDm; Object Layer Attributes #2, Allright_Stavebni_dil_ID: 1852Stě0798433609; Object Layer Attributes #2, Jednotka: m3; Object Layer Attributes #2, Název_objektu: Stěna; Object Layer Attributes #2, Staticky nosná konstrukce: yes
ZDIVO Z CDm | Půdorys 5.NP | EPS 0.1 m, ZDIVO Z CDm 0.5 m |  | ZDIVO Z CDm | A | 1852HWa0000000002 | m3 | Celá stěna | Stávající | Zateplovací systémy | EPS | no | 1852Stě0000001511 | m2 | Stěna | 0 | 0.6 | 16.716 | 16.716 | 9.318 | 4.15 | 9.318 | 2.47 | 3.98 | NEMSOK - Object Layer Attributes #2, 2D interakce: yes; Object Layer Attributes #2, Status: Stávající; Object Layer Attributes #2, Práce: Zednické práce; Object Layer Attributes #2, Materiál: ZDIVO Z CDm; Object Layer Attributes #2, Allright_Stavebni_dil_ID: 1852Stě0798434294; Object Layer Attributes #2, Jednotka: m3; Object Layer Attributes #2, Název_objektu: Stěna; Object Layer Attributes #2, Staticky nosná konstrukce: yes
ZDIVO Z CDm | Půdorys 5.NP | EPS 0.1 m, ZDIVO Z CDm 0.5 m | 1 | ZDIVO Z CDm | A | 1852HWa0000000014 | m3 | Celá stěna | Stávající | Zateplovací systémy | EPS | no | 1852Stě0000001380 | m2 | Stěna | 0 | 0.6 | 34.427 | 34.427 | 18.456 | 8.35 | 18.456 | 4.89 | 3.98 | NEMSOK - Object Layer Attributes #2, 2D interakce: yes; Object Layer Attributes #2, Status: Stávající; Object Layer Attributes #2, Práce: Zednické práce; Object Layer Attributes #2, Materiál: ZDIVO Z CDm; Object Layer Attributes #2, Allright_Stavebni_dil_ID: 1852Stě0798434341; Object Layer Attributes #2, Jednotka: m3; Object Layer Attributes #2, Název_objektu: Stěna; Object Layer Attributes #2, Staticky nosná konstrukce: yes
ZDIVO Z CDm | Půdorys 5.NP | EPS 0.1 m, ZDIVO Z CDm 0.5 m | 1 | ZDIVO Z CDm | A | 1852HWa0000000008 | m3 | Celá stěna | Stávající | Zateplovací systémy | EPS | no | 1852Stě0000001374 | m2 | Stěna | 0 | 0.6 | 14.328 | 14.328 | 7.214 | 3.35 | 7.214 | 1.91 | 3.98 | NEMSOK - Object Layer Attributes #2, 2D interakce: yes; Object Layer Attributes #2, Status: Stávající; Object Layer Attributes #2, Práce: Zednické práce; Object Layer Attributes #2, Materiál: ZDIVO Z CDm; Object Layer Attributes #2, Allright_Stavebni_dil_ID: 1852Stě0798434383; Object Layer Attributes #2, Jednotka: m3; Object Layer Attributes #2, Název_objektu: Stěna; Object Layer Attributes #2, Staticky nosná konstrukce: yes
ZDIVO Z CDm | Půdorys 5.NP | EPS 0.1 m, ZDIVO Z CDm 0.5 m | 1 | ZDIVO Z CDm | A | 1852HWa0000006238 | m3 | Celá stěna | Stávající | Zateplovací systémy | EPS | no | 1852Stě0000006240 | m2 | Stěna | 0 | 0.6 | 17.4 | 17.4 | 10.31 | 3.75 | 10.31 | 2.35 | 4.6 | NEMSOK - Object Layer Attributes #2, 2D interakce: yes; Object Layer Attributes #2, Status: Stávající; Object Layer Attributes #2, Práce: Zednické práce; Object Layer Attributes #2, Materiál: ZDIVO Z CDm; Object Layer Attributes #2, Allright_Stavebni_dil_ID: 1852Stě0798434423; Object Layer Attributes #2, Jednotka: m3; Object Layer Attributes #2, Název_objektu: Stěna; Object Layer Attributes #2, Staticky nosná konstrukce: yes
ZDIVO Z CDm | Půdorys 5.NP | ZDIVO Z CDm 0.5 m |  | ZDIVO Z CDm | A | 1852HWa0798434460 | m3 | Celá stěna | Stávající | Zednické práce | ZDIVO Z CDm | yes | 1852Stě0798434468 | m3 | Stěna | 0 | 0.5 | 21.532 | 16.151 | 10.766 | 4.95 | 8.075 | 2.475 | 4.35
ZDIVO Z CDm | Půdorys 5.NP | EPS 0.1 m, ZDIVO Z CDm 0.5 m | 1 | ZDIVO Z CDm | A | 1852HWa0000000019 | m3 | Celá stěna | Stávající | Zateplovací systémy | EPS | no | 1852Stě0000001491 | m2 | Stěna | 0 | 0.6 | 3.68 | 3.68 | 2.108 | 0.8 | 2.108 | 0.48 | 4.6 | NEMSOK - Object Layer Attributes #2, 2D interakce: yes; Object Layer Attributes #2, Status: Stávající; Object Layer Attributes #2, Práce: Zednické práce; Object Layer Attributes #2, Materiál: ZDIVO Z CDm; Object Layer Attributes #2, Allright_Stavebni_dil_ID: 1852Stě0798434505; Object Layer Attributes #2, Jednotka: m3; Object Layer Attributes #2, Název_objektu: Stěna; Object Layer Attributes #2, Staticky nosná konstrukce: yes
ZDIVO Z CDm | Půdorys 5.NP | EPS |  | ZDIVO Z CDm | A | 1852HWa0000000006 | m3 | Celá stěna | Stávající | Zateplovací systémy | EPS | no | 1852Stě0000001378 | m2 | Stěna | 0 | 0.6 | 14.35 | 5.415 | 7.742 | 3.2 | 3.218 | 1.8 | 4.35 | NEMSOK - Object Layer Attributes #2, 2D interakce: yes; Object Layer Attributes #2, Status: Stávající; Object Layer Attributes #2, Práce: Zednické práce; Object Layer Attributes #2, Materiál: ZDIVO Z CDm; Object Layer Attributes #2, Allright_Stavebni_dil_ID: 1852Stě0798434592; Object Layer Attributes #2, Jednotka: m3; Object Layer Attributes #2, Název_objektu: Stěna; Object Layer Attributes #2, Staticky nosná konstrukce: yes
ZDIVO Z CDm | Půdorys 5.NP | ZDIVO Z CDm 0.15 m |  | ZDIVO Z CDm | A | 1852HWa0798435126 | m3 | Celá stěna | Stávající | Zednické práce | ZDIVO Z CDm | no | 1852Stě0798435136 | m3 | Stěna | 0 | 0.15 | 0.157 | 0.158 | 0.024 | 0.45 | 0.024 | 0.068 | 0.35
ZDIVO Z CDm | Půdorys 5.NP | ZDIVO Z CDm 0.15 m |  | ZDIVO Z CDm | A | 1852HWa0798435131 | m3 | Celá stěna | Stávající | Zednické práce | ZDIVO Z CDm | no | 1852Stě0798435138 | m3 | Stěna | 0 | 0.15 | 0.158 | 0.158 | 0.024 | 0.45 | 0.024 | 0.068 | 0.35
ZDIVO Z CDm | Půdorys 5.NP | ZDIVO Z CDm 0.15 m |  | ZDIVO Z CDm | A | 1852HWa0798435127 | m3 | Celá stěna | Stávající | Zednické práce | ZDIVO Z CDm | no | 1852Stě0798435137 | m3 | Stěna | 0 | 0.15 | 0.157 | 0.158 | 0.024 | 0.45 | 0.024 | 0.068 | 0.35
ZDIVO Z CDm | Půdorys 5.NP | ZDIVO Z CDm 0.15 m |  | ZDIVO Z CDm | A | 1852HWa0798435128 | m3 | Celá stěna | Stávající | Zednické práce | ZDIVO Z CDm | no | 1852Stě0798435134 | m3 | Stěna | 0 | 0.15 | 0.158 | 0.158 | 0.024 | 0.45 | 0.024 | 0.068 | 0.35
ZDIVO Z CDm | Půdorys 5.NP | ZDIVO Z CDm 0.15 m | 1 | ZDIVO Z CDm | A | 1852HWa0798428854 | m3 | Celá stěna | Stávající | Zednické práce | ZDIVO Z CDm | no | 1852Stě0798428855 | m3 | Stěna | 0 | 0.15 | 0.855 | 0.855 | 0.128 | 0.9 | 0.128 | 0.135 | 0.95
ZDIVO Z CDm | Půdorys 5.NP | ZDIVO Z CDm 0.15 m | 1 | ZDIVO Z CDm | A | 1852HWa0798428827 | m3 | Celá stěna | Stávající | Zednické práce | ZDIVO Z CDm | no | 1852Stě0798428828 | m3 | Stěna | 0 | 0.15 | 0.808 | 0.808 | 0.121 | 0.85 | 0.121 | 0.128 | 0.95
ZDIVO Z CDm | Půdorys 5.NP | ZDIVO Z CDm 0.15 m |  | ZDIVO Z CDm | A | 1852HWa0798428842 | m3 | Celá stěna | Stávající | Zednické práce | ZDIVO Z CDm | no | 1852Stě0798428843 | m3 | Stěna | 0 | 0.15 | 0.665 | 0.665 | 0.1 | 0.7 | 0.1 | 0.105 | 0.95
ZELEZOBETONOVÁ KCE | Půdorys 5.NP | ZELEZOBETONOVÁ KCE 0.2 m |  | ZELEZOBETONOVÁ KCE | A | 1852HWa0798427150 | m3 | Celá stěna | Stávající | Betonářské práce | ZELEZOBETONOVÁ KCE | no | 1852Stě0798427151 | m3 | Stěna | 0 | 0.2 | 14.867 | 14.44 | 2.973 | 15.65 | 2.888 | 3.13 | 0.95
ZDIVO Z CDm | Půdorys 5.NP | EPS 0.1 m, ZDIVO Z CDm 0.25 m |  | ZDIVO Z CDm | A | 1852HWa0798427201 | m3 | Celá stěna | Stávající | Zateplovací systémy | EPS | no | 1852Stě0798427202 | m2 | Stěna | 0 | 0.35 | 1.785 | 1.785 | 0.625 | 2.1 | 0.625 | 0.735 | 0.85 | NEMSOK - Object Layer Attributes #2, 2D interakce: yes; Object Layer Attributes #2, Status: Stávající; Object Layer Attributes #2, Práce: Zednické práce; Object Layer Attributes #2, Materiál: ZDIVO Z CDm; Object Layer Attributes #2, Allright_Stavebni_dil_ID: 1852Stě0798429436; Object Layer Attributes #2, Jednotka: m3; Object Layer Attributes #2, Název_objektu: Stěna; Object Layer Attributes #2, Staticky nosná konstrukce: no
ZDIVO Z CDm | Půdorys 5.NP | ZDIVO Z CDm 0.32 m |  | ZDIVO Z CDm | A | 1852HWa0798427047 | m3 | Celá stěna | Stávající | Zednické práce | ZDIVO Z CDm | yes | 1852Stě0798427048 | m3 | Stěna | 0 | 0.32 | 2.451 | 2.406 | 0.784 | 2.58 | 0.77 | 0.826 | 0.95
ZDIVO Z CDm | Půdorys 5.NP | ZDIVO Z CDm 0.2 m |  | ZDIVO Z CDm | A | 1852HWa0798428585 | m3 | Celá stěna | Stávající | Zednické práce | ZDIVO Z CDm | yes | 1852Stě0798428586 | m3 | Stěna | 0 | 0.2 | 0.76 | 0.689 | 0.152 | 0.8 | 0.138 | 0.16 | 0.95
ZDIVO Z CDm | Půdorys 5.NP | ZDIVO Z CDm 0.2 m | 1 | ZDIVO Z CDm | A | 1852HWa0798428611 | m3 | Celá stěna | Stávající | Zednické práce | ZDIVO Z CDm | yes | 1852Stě0798428612 | m3 | Stěna | 0 | 0.2 | 0.76 | 0.689 | 0.152 | 0.8 | 0.138 | 0.16 | 0.95
ZDIVO Z CDm | Půdorys 5.NP | ZDIVO Z CDm 0.25 m |  | ZDIVO Z CDm | A | 1852HWa0798427120 | m3 | Celá stěna | Stávající | Zednické práce | ZDIVO Z CDm | yes | 1852Stě0798427121 | m3 | Stěna | 0 | 0.25 | 3.42 | 3.42 | 0.855 | 3.6 | 0.855 | 0.9 | 0.95
ZDIVO Z CDm | Půdorys 5.NP | ZDIVO Z CDm 0.25 m |  | ZDIVO Z CDm | A | 1852HWa0798427110 | m3 | Celá stěna | Stávající | Zednické práce | ZDIVO Z CDm | yes | 1852Stě0798427111 | m3 | Stěna | 0 | 0.25 | 2.232 | 2.188 | 0.558 | 2.35 | 0.547 | 0.588 | 0.95
ZDIVO Z CDm | Půdorys 5.NP | ZDIVO Z CDm 0.25 m |  | ZDIVO Z CDm | A | 1852HWa0798429081 | m3 | Celá stěna | Stávající | Zednické práce | ZDIVO Z CDm | yes | 1852Stě0798429083 | m3 | Stěna | 0 | 0.25 | 6.3 | 6.232 | 1.575 | 3.6 | 1.558 | 0.9 | 1.75
ZDIVO Z CDm | Půdorys 5.NP | ZDIVO Z CDm 0.25 m |  | ZDIVO Z CDm | A | 1852HWa0798429098 | m3 | Celá stěna | Stávající | Zednické práce | ZDIVO Z CDm | yes | 1852Stě0798429100 | m3 | Stěna | 0 | 0.25 | 6.375 | 6.33 | 1.594 | 2.5 | 1.583 | 0.625 | 2.55
ZELEZOBETONOVÁ KCE | Půdorys 5.NP | ZELEZOBETONOVÁ KCE 0.3 m | 1 | ZELEZOBETONOVÁ KCE | A | 1852HWa0798427155 | m3 | Celá stěna | Stávající | Betonářské práce | ZELEZOBETONOVÁ KCE | no | 1852Stě0798427156 | m3 | Stěna | 0 | 0.3 | 0.969 | 0.969 | 0.291 | 1.02 | 0.291 | 0.306 | 0.95
ZELEZOBETONOVÁ KCE | Půdorys 5.NP | ZELEZOBETONOVÁ KCE 0.32 m | 1 | ZELEZOBETONOVÁ KCE | A | 1852HWa0798427249 | m3 | Celá stěna | Stávající | Betonářské práce | ZELEZOBETONOVÁ KCE | no | 1852Stě0798427250 | m3 | Stěna | 0 | 0.32 | 30.78 | 30.172 | 9.85 | 32.4 | 9.655 | 10.368 | 0.95
ZELEZOBETONOVÁ KCE | Půdorys 5.NP | ZELEZOBETONOVÁ KCE 0.3 m | 1 | ZELEZOBETONOVÁ KCE | A | 1852HWa0798427225 | m3 | Celá stěna | Stávající | Betonářské práce | ZELEZOBETONOVÁ KCE | no | 1852Stě0798427226 | m3 | Stěna | 0 | 0.3 | 0.969 | 0.969 | 0.291 | 1.02 | 0.291 | 0.306 | 0.95
ZELEZOBETONOVÁ KCE | Půdorys 5.NP | ZELEZOBETONOVÁ KCE 0.2 m | 1 | ZELEZOBETONOVÁ KCE | A | 1852HWa0798426170 | m3 | Celá stěna | Stávající | Betonářské práce | ZELEZOBETONOVÁ KCE |  | 1852Stě0798426171 | m3 | Stěna | 0 | 0.2 | 4.56 | 4.447 | 0.912 | 4.8 | 0.889 | 0.96 | 0.95
ZELEZOBETONOVÁ KCE | Půdorys 5.NP | ZELEZOBETONOVÁ KCE 0.2 m |  | ZELEZOBETONOVÁ KCE | A | 1852HWa0798426123 | m3 | Celá stěna | Stávající | Betonářské práce | ZELEZOBETONOVÁ KCE |  | 1852Stě0798426124 | m3 | Stěna | 0 | 0.2 | 4.56 | 4.447 | 0.912 | 4.8 | 0.89 | 0.96 | 0.95
ZELEZOBETONOVÁ KCE | Půdorys 5.NP | ZELEZOBETONOVÁ KCE 0.3 m |  | ZELEZOBETONOVÁ KCE | A | 1852HWa0798427030 | m3 | Celá stěna | Stávající | Betonářské práce | ZELEZOBETONOVÁ KCE | no | 1852Stě0798427031 | m3 | Stěna | 0 | 0.3 | 0.969 | 0.969 | 0.291 | 1.02 | 0.291 | 0.306 | 0.95
ZELEZOBETONOVÁ KCE | Půdorys 5.NP | ZELEZOBETONOVÁ KCE 0.3 m |  | ZELEZOBETONOVÁ KCE | A | 1852HWa0000007333 | m3 | Celá stěna | Stávající | Betonářské práce | ZELEZOBETONOVÁ KCE |  | 1852Stě0000007334 | m3 | Stěna | 0 | 0.3 | 1.712 | 1.713 | 0.514 | 1.37 | 0.514 | 0.411 | 1.25
ZELEZOBETONOVÁ KCE | Půdorys 5.NP | ZELEZOBETONOVÁ KCE 0.3 m |  | ZELEZOBETONOVÁ KCE | A | 1852HWa0000007312 | m3 | Celá stěna | Stávající | Betonářské práce | ZELEZOBETONOVÁ KCE |  | 1852Stě0000007313 | m3 | Stěna | 0 | 0.3 | 1.275 | 1.275 | 0.383 | 1.02 | 0.383 | 0.306 | 1.25
ZELEZOBETONOVÁ KCE | Půdorys 5.NP | ZELEZOBETONOVÁ KCE 0.32 m |  | ZELEZOBETONOVÁ KCE | A | 1852HWa0000007322 | m3 | Celá stěna | Stávající | Betonářské práce | ZELEZOBETONOVÁ KCE |  | 1852Stě0000007323 | m3 | Stěna | 0 | 0.32 | 19.5 | 19.207 | 6.24 | 15.6 | 6.146 | 4.992 | 1.25
ZELEZOBETONOVÁ KCE | Půdorys 5.NP | ZELEZOBETONOVÁ KCE 0.3 m | 1 | ZELEZOBETONOVÁ KCE | A | 1852HWa0798427092 | m3 | Celá stěna | Stávající | Betonářské práce | ZELEZOBETONOVÁ KCE | no | 1852Stě0798427093 | m3 | Stěna | 0 | 0.3 | 0.969 | 0.969 | 0.291 | 1.02 | 0.291 | 0.306 | 0.95
ZELEZOBETONOVÁ KCE | Půdorys 5.NP | ZELEZOBETONOVÁ KCE 0.3 m |  | ZELEZOBETONOVÁ KCE | A | 1852HWa0000007317 | m3 | Celá stěna | Stávající | Betonářské práce | ZELEZOBETONOVÁ KCE |  | 1852Stě0000007318 | m3 | Stěna | 0 | 0.3 | 1.275 | 1.275 | 0.382 | 1.02 | 0.382 | 0.306 | 1.25
ZDIVO Z CDm | Půdorys 5.NP | ZDIVO Z CDm 0.32 m | 1 | ZDIVO Z CDm | A | 1852HWa0798428509 | m3 | Celá stěna | Stávající | Zednické práce | ZDIVO Z CDm | yes | 1852Stě0798428510 | m3 | Stěna | 0 | 0.32 | 0.171 | 0.171 | 0.055 | 0.18 | 0.055 | 0.058 | 0.95
ZELEZOBETONOVÁ KCE | Půdorys 5.NP | ZELEZOBETONOVÁ KCE 0.3 m |  | ZELEZOBETONOVÁ KCE | A | 1852HWa0000007343 | m3 | Celá stěna | Stávající | Betonářské práce | ZELEZOBETONOVÁ KCE |  | 1852Stě0000007344 | m3 | Stěna | 0 | 0.3 | 1.712 | 1.713 | 0.514 | 1.37 | 0.514 | 0.411 | 1.25
ZELEZOBETONOVÁ KCE | Půdorys 5.NP | ZELEZOBETONOVÁ KCE 0.32 m | 1 | ZELEZOBETONOVÁ KCE | A | 1852HWa0798427097 | m3 | Celá stěna | Stávající | Betonářské práce | ZELEZOBETONOVÁ KCE | no | 1852Stě0798427098 | m3 | Stěna | 0 | 0.32 | 7.98 | 7.822 | 2.554 | 8.4 | 2.503 | 2.688 | 0.95
ZDIVO Z CDm | Půdorys 5.NP | ZDIVO Z CDm 0.25 m |  | ZDIVO Z CDm | A | 1852HWa0798429230 | m3 | Celá stěna | Stávající | Zednické práce | ZDIVO Z CDm | yes | 1852Stě0798429232 | m3 | Stěna | 0 | 0.25 | 1.045 | 1.022 | 0.261 | 1.1 | 0.256 | 0.275 | 0.95
 | Půdorys 5.NP | ZELEZOBETONOVÁ KCE 0.5 m |  |  |  | 1854HWa0000000052 | m3 | Celá stěna | Stávající | Betonářské práce | ZELEZOBETONOVÁ KCE | yes | 1854Ven0000000055 | m2 | Věnec |  | 0.5 | 0.525 | 0.525 | 0.263 | 0 | 0.263 | 1.05 | 0.25
 | Půdorys 5.NP | ZELEZOBETONOVÁ KCE 0.5 m |  |  |  | 1854HWa0000000196 | m3 | Celá stěna | Stávající | Betonářské práce | ZELEZOBETONOVÁ KCE | yes | 1854Ven0000000198 | m2 | Věnec |  | 0.5 | 1.888 | 1.888 | 0.944 | 0 | 0.944 | 3.775 | 0.25
 | Půdorys 5.NP | ZELEZOBETONOVÁ KCE 0.5 m |  |  |  | 1854HWa0000000012 | m3 | Celá stěna | Stávající | Betonářské práce | ZELEZOBETONOVÁ KCE | yes | 1854Ven0000000027 | m2 | Věnec |  | 0.5 | 1.888 | 1.888 | 0.944 | 0 | 0.944 | 3.775 | 0.25
 | Půdorys 5.NP | ZELEZOBETONOVÁ KCE 0.5 m |  |  |  | 1854HWa0000000007 | m3 | Celá stěna | Stávající | Betonářské práce | ZELEZOBETONOVÁ KCE | yes | 1854Ven0000000067 | m2 | Věnec |  | 0.5 | 0.75 | 0.75 | 0.375 | 0 | 0.375 | 1.5 | 0.25
 | Půdorys 5.NP | HERAKLIT 0.05 m, ZELEZOBETONOVÁ KCE 0.2 m | 1 |  |  | 1854HWa0000001419 | m3 | Celá stěna | Stávající | Zateplovací systémy | HERAKLIT | no | 1854Ven0000001420 | m2 | Věnec |  | 0.25 | 0.35 | 0.35 | 0.085 | 0 | 0.085 | 0.34 | 0.25 | NEMSOK - Object Layer Attributes #2, 2D interakce: yes; Object Layer Attributes #2, Status: Stávající; Object Layer Attributes #2, Práce: Betonářské práce; Object Layer Attributes #2, Materiál: ZELEZOBETONOVÁ KCE; Object Layer Attributes #2, Allright_Stavebni_dil_ID: 1854Ven0000001421; Object Layer Attributes #2, Jednotka: m2; Object Layer Attributes #2, Název_objektu: Věnec; Object Layer Attributes #2, Staticky nosná konstrukce: yes
 | Půdorys 5.NP | HERAKLIT 0.05 m, ZELEZOBETONOVÁ KCE 0.2 m | 1 |  |  | 1854HWa0000001427 | m3 | Celá stěna | Stávající | Zateplovací systémy | HERAKLIT | no | 1854Ven0000001428 | m2 | Věnec |  | 0.25 | 2.862 | 2.863 | 0.703 | 0 | 0.703 | 2.812 | 0.25 | NEMSOK - Object Layer Attributes #2, 2D interakce: yes; Object Layer Attributes #2, Status: Stávající; Object Layer Attributes #2, Práce: Betonářské práce; Object Layer Attributes #2, Materiál: ZELEZOBETONOVÁ KCE; Object Layer Attributes #2, Allright_Stavebni_dil_ID: 1854Ven0000001429; Object Layer Attributes #2, Jednotka: m2; Object Layer Attributes #2, Název_objektu: Věnec; Object Layer Attributes #2, Staticky nosná konstrukce: yes
 | Půdorys 5.NP | HERAKLIT 0.05 m, ZELEZOBETONOVÁ KCE 0.2 m | 1 |  |  | 1854HWa0000001485 | m3 | Celá stěna | Stávající | Zateplovací systémy | HERAKLIT | no | 1854Ven0000001486 | m2 | Věnec |  | 0.25 | 2.862 | 2.863 | 0.703 | 0 | 0.703 | 2.813 | 0.25 | NEMSOK - Object Layer Attributes #2, 2D interakce: yes; Object Layer Attributes #2, Status: Stávající; Object Layer Attributes #2, Práce: Betonářské práce; Object Layer Attributes #2, Materiál: ZELEZOBETONOVÁ KCE; Object Layer Attributes #2, Allright_Stavebni_dil_ID: 1854Ven0000001487; Object Layer Attributes #2, Jednotka: m2; Object Layer Attributes #2, Název_objektu: Věnec; Object Layer Attributes #2, Staticky nosná konstrukce: yes
 | Půdorys 5.NP | HERAKLIT 0.05 m, ZELEZOBETONOVÁ KCE 0.2 m | 1 |  |  | 1854HWa0000001512 | m3 | Celá stěna | Stávající | Zateplovací systémy | HERAKLIT | no | 1854Ven0000001513 | m2 | Věnec |  | 0.25 | 0.3 | 0.3 | 0.074 | 0 | 0.074 | 0.298 | 0.25 | NEMSOK - Object Layer Attributes #2, 2D interakce: yes; Object Layer Attributes #2, Status: Stávající; Object Layer Attributes #2, Práce: Betonářské práce; Object Layer Attributes #2, Materiál: ZELEZOBETONOVÁ KCE; Object Layer Attributes #2, Allright_Stavebni_dil_ID: 1854Ven0000001514; Object Layer Attributes #2, Jednotka: m2; Object Layer Attributes #2, Název_objektu: Věnec; Object Layer Attributes #2, Staticky nosná konstrukce: yes
 | Půdorys 5.NP | HERAKLIT 0.05 m, ZELEZOBETONOVÁ KCE 0.25 m | 1 |  |  | 1854HWa0000001547 | m3 | Celá stěna | Stávající | Zateplovací systémy | HERAKLIT | no | 1854Ven0000001548 | m2 | Věnec |  | 0.3 | 1.787 | 1.788 | 0.536 | 0 | 0.536 | 2.145 | 0.25 | NEMSOK - Object Layer Attributes #2, 2D interakce: yes; Object Layer Attributes #2, Status: Stávající; Object Layer Attributes #2, Práce: Betonářské práce; Object Layer Attributes #2, Materiál: ZELEZOBETONOVÁ KCE; Object Layer Attributes #2, Allright_Stavebni_dil_ID: 1854Ven0000001549; Object Layer Attributes #2, Jednotka: m2; Object Layer Attributes #2, Název_objektu: Věnec; Object Layer Attributes #2, Staticky nosná konstrukce: yes
 | Půdorys 5.NP | HERAKLIT 0.05 m, ZELEZOBETONOVÁ KCE 0.25 m | 1 |  |  | 1854HWa0000001593 | m3 | Celá stěna | Stávající | Zateplovací systémy | HERAKLIT | no | 1854Ven0000001594 | m2 | Věnec |  | 0.3 | 0.5 | 0.5 | 0.149 | 0 | 0.149 | 0.597 | 0.25 | NEMSOK - Object Layer Attributes #2, 2D interakce: yes; Object Layer Attributes #2, Status: Stávající; Object Layer Attributes #2, Práce: Betonářské práce; Object Layer Attributes #2, Materiál: ZELEZOBETONOVÁ KCE; Object Layer Attributes #2, Allright_Stavebni_dil_ID: 1854Ven0000001595; Object Layer Attributes #2, Jednotka: m2; Object Layer Attributes #2, Název_objektu: Věnec; Object Layer Attributes #2, Staticky nosná konstrukce: yes
 | Půdorys 5.NP | HERAKLIT 0.05 m, ZELEZOBETONOVÁ KCE 0.25 m | 1 |  |  | 1854HWa0000001677 | m3 | Celá stěna | Stávající | Zateplovací systémy | HERAKLIT | no | 1854Ven0000001683 | m2 | Věnec |  | 0.3 | 0.938 | 0.938 | 0.266 | 0 | 0.266 | 1.063 | 0.25 | NEMSOK - Object Layer Attributes #2, 2D interakce: yes; Object Layer Attributes #2, Status: Stávající; Object Layer Attributes #2, Práce: Betonářské práce; Object Layer Attributes #2, Materiál: ZELEZOBETONOVÁ KCE; Object Layer Attributes #2, Allright_Stavebni_dil_ID: 1854Ven0000001682; Object Layer Attributes #2, Jednotka: m2; Object Layer Attributes #2, Název_objektu: Věnec; Object Layer Attributes #2, Staticky nosná konstrukce: yes
 | Půdorys 5.NP | HERAKLIT 0.05 m, ZELEZOBETONOVÁ KCE 0.15 m | 1 |  |  | 1854HWa0000001638 | m3 | Celá stěna | Stávající | Zateplovací systémy | HERAKLIT | no | 1854Ven0000001643 | m2 | Věnec |  | 0.2 | 0.35 | 0.35 | 0.07 | 0 | 0.07 | 0.28 | 0.25 | NEMSOK - Object Layer Attributes #2, 2D interakce: yes; Object Layer Attributes #2, Status: Stávající; Object Layer Attributes #2, Práce: Betonářské práce; Object Layer Attributes #2, Materiál: ZELEZOBETONOVÁ KCE; Object Layer Attributes #2, Allright_Stavebni_dil_ID: 1854Ven0000001642; Object Layer Attributes #2, Jednotka: m2; Object Layer Attributes #2, Název_objektu: Věnec; Object Layer Attributes #2, Staticky nosná konstrukce: yes
 | Půdorys 5.NP | HERAKLIT 0.05 m, ZELEZOBETONOVÁ KCE 0.25 m |  |  |  | 1854HWa0000001568 | m3 | Celá stěna | Stávající | Zateplovací systémy | HERAKLIT | no | 1854Ven0000001569 | m2 | Věnec |  | 0.3 | 3.487 | 3.488 | 1.027 | 0 | 1.027 | 4.11 | 0.25 | NEMSOK - Object Layer Attributes #2, 2D interakce: yes; Object Layer Attributes #2, Status: Stávající; Object Layer Attributes #2, Práce: Betonářské práce; Object Layer Attributes #2, Materiál: ZELEZOBETONOVÁ KCE; Object Layer Attributes #2, Allright_Stavebni_dil_ID: 1854Ven0000001570; Object Layer Attributes #2, Jednotka: m2; Object Layer Attributes #2, Název_objektu: Věnec; Object Layer Attributes #2, Staticky nosná konstrukce: yes
 | Půdorys 5.NP | HERAKLIT 0.05 m, ZELEZOBETONOVÁ KCE 0.2 m |  |  |  | 1854HWa0000001450 | m3 | Celá stěna | Stávající | Zateplovací systémy | HERAKLIT | no | 1854Ven0000001451 | m2 | Věnec |  | 0.25 | 4.062 | 4.063 | 1.003 | 0 | 1.003 | 4.013 | 0.25 | NEMSOK - Object Layer Attributes #2, 2D interakce: yes; Object Layer Attributes #2, Status: Stávající; Object Layer Attributes #2, Práce: Betonářské práce; Object Layer Attributes #2, Materiál: ZELEZOBETONOVÁ KCE; Object Layer Attributes #2, Allright_Stavebni_dil_ID: 1854Ven0000001452; Object Layer Attributes #2, Jednotka: m2; Object Layer Attributes #2, Název_objektu: Věnec; Object Layer Attributes #2, Staticky nosná konstrukce: yes
 | Půdorys 5.NP | ZELEZOBETONOVÁ KCE 0.45 m, LIGNOPOR 0.05 m |  |  |  | 1854HWa0000000002 | m3 | Celá stěna | Stávající | Betonářské práce | ZELEZOBETONOVÁ KCE | yes | 1854Ven0000000017 | m2 | Věnec |  | 0.5 | 0.837 | 0.838 | 0.362 | 0 | 0.362 | 1.45 | 0.25 | NEMSOK - Object Layer Attributes #2, 2D interakce: yes; Object Layer Attributes #2, Status: Stávající; Object Layer Attributes #2, Práce: Zateplovací systémy; Object Layer Attributes #2, Materiál: LIGNOPOR; Object Layer Attributes #2, Allright_Stavebni_dil_ID: 1854Ven0000000015; Object Layer Attributes #2, Jednotka: m2; Object Layer Attributes #2, Název_objektu: Věnec; Object Layer Attributes #2, Staticky nosná konstrukce: no
 | Půdorys 5.NP | ZELEZOBETONOVÁ KCE 0.45 m, LIGNOPOR 0.05 m |  |  |  | 1854HWa0000000004 | m3 | Celá stěna | Stávající | Betonářské práce | ZELEZOBETONOVÁ KCE | yes | 1854Ven0000000025 | m2 | Věnec |  | 0.5 | 0.188 | 0.188 | 0.049 | 0 | 0.049 | 0.195 | 0.25 | NEMSOK - Object Layer Attributes #2, 2D interakce: yes; Object Layer Attributes #2, Status: Stávající; Object Layer Attributes #2, Práce: Zateplovací systémy; Object Layer Attributes #2, Materiál: LIGNOPOR; Object Layer Attributes #2, Allright_Stavebni_dil_ID: 1854Ven0000000029; Object Layer Attributes #2, Jednotka: m2; Object Layer Attributes #2, Název_objektu: Věnec; Object Layer Attributes #2, Staticky nosná konstrukce: no
 | Půdorys 5.NP | ZELEZOBETONOVÁ KCE 0.45 m, LIGNOPOR 0.05 m |  |  |  | 1854HWa0000000005 | m3 | Celá stěna | Stávající | Betonářské práce | ZELEZOBETONOVÁ KCE | yes | 1854Ven0000000035 | m2 | Věnec |  | 0.5 | 1 | 1 | 0.494 | 0 | 0.494 | 1.977 | 0.25 | NEMSOK - Object Layer Attributes #2, 2D interakce: yes; Object Layer Attributes #2, Status: Stávající; Object Layer Attributes #2, Práce: Zateplovací systémy; Object Layer Attributes #2, Materiál: LIGNOPOR; Object Layer Attributes #2, Allright_Stavebni_dil_ID: 1854Ven0000000033; Object Layer Attributes #2, Jednotka: m2; Object Layer Attributes #2, Název_objektu: Věnec; Object Layer Attributes #2, Staticky nosná konstrukce: no
 | Půdorys 5.NP | ZELEZOBETONOVÁ KCE 0.45 m, LIGNOPOR 0.05 m |  |  |  | 1854HWa0000000030 | m3 | Celá stěna | Stávající | Betonářské práce | ZELEZOBETONOVÁ KCE | yes | 1854Ven0000000065 | m2 | Věnec |  | 0.5 | 0.888 | 0.888 | 0.393 | 0 | 0.393 | 1.573 | 0.25 | NEMSOK - Object Layer Attributes #2, 2D interakce: yes; Object Layer Attributes #2, Status: Stávající; Object Layer Attributes #2, Práce: Zateplovací systémy; Object Layer Attributes #2, Materiál: LIGNOPOR; Object Layer Attributes #2, Allright_Stavebni_dil_ID: 1854Ven0000000039; Object Layer Attributes #2, Jednotka: m2; Object Layer Attributes #2, Název_objektu: Věnec; Object Layer Attributes #2, Staticky nosná konstrukce: no
 | Půdorys 5.NP | ZELEZOBETONOVÁ KCE 0.45 m, LIGNOPOR 0.05 m |  |  |  | 1854HWa0000000036 | m3 | Celá stěna | Stávající | Betonářské práce | ZELEZOBETONOVÁ KCE | yes | 1854Ven0000000047 | m2 | Věnec |  | 0.5 | 2.138 | 2.138 | 1.058 | 0 | 1.058 | 4.23 | 0.25 | NEMSOK - Object Layer Attributes #2, 2D interakce: yes; Object Layer Attributes #2, Status: Stávající; Object Layer Attributes #2, Práce: Zateplovací systémy; Object Layer Attributes #2, Materiál: LIGNOPOR; Object Layer Attributes #2, Allright_Stavebni_dil_ID: 1854Ven0000000045; Object Layer Attributes #2, Jednotka: m2; Object Layer Attributes #2, Název_objektu: Věnec; Object Layer Attributes #2, Staticky nosná konstrukce: no
 | Půdorys 5.NP | ZELEZOBETONOVÁ KCE 0.45 m, LIGNOPOR 0.05 m |  |  |  | 1854HWa0000000040 | m3 | Celá stěna | Stávající | Betonářské práce | ZELEZOBETONOVÁ KCE | yes | 1854Ven0000000063 | m2 | Věnec |  | 0.5 | 1.012 | 1.013 | 0.456 | 0 | 0.456 | 1.822 | 0.25 | NEMSOK - Object Layer Attributes #2, 2D interakce: yes; Object Layer Attributes #2, Status: Stávající; Object Layer Attributes #2, Práce: Zateplovací systémy; Object Layer Attributes #2, Materiál: LIGNOPOR; Object Layer Attributes #2, Allright_Stavebni_dil_ID: 1854Ven0000000043; Object Layer Attributes #2, Jednotka: m2; Object Layer Attributes #2, Název_objektu: Věnec; Object Layer Attributes #2, Staticky nosná konstrukce: no
 | Půdorys 5.NP | ZELEZOBETONOVÁ KCE 0.45 m, LIGNOPOR 0.05 m |  |  |  | 1854HWa0000000011 | m3 | Celá stěna | Stávající | Betonářské práce | ZELEZOBETONOVÁ KCE | yes | 1854Ven0000000049 | m2 | Věnec |  | 0.5 | 1.725 | 1.725 | 0.857 | 0 | 0.857 | 3.428 | 0.25 | NEMSOK - Object Layer Attributes #2, 2D interakce: yes; Object Layer Attributes #2, Status: Stávající; Object Layer Attributes #2, Práce: Zateplovací systémy; Object Layer Attributes #2, Materiál: LIGNOPOR; Object Layer Attributes #2, Allright_Stavebni_dil_ID: 1854Ven0000000051; Object Layer Attributes #2, Jednotka: m2; Object Layer Attributes #2, Název_objektu: Věnec; Object Layer Attributes #2, Staticky nosná konstrukce: no
 | Půdorys 5.NP | ZELEZOBETONOVÁ KCE 0.45 m, LIGNOPOR 0.05 m |  |  |  | 1854HWa0000000009 | m3 | Celá stěna | Stávající | Betonářské práce | ZELEZOBETONOVÁ KCE | yes | 1854Ven0000000020 | m2 | Věnec |  | 0.5 | 2.325 | 2.325 | 1.106 | 0 | 1.106 | 4.425 | 0.25 | NEMSOK - Object Layer Attributes #2, 2D interakce: yes; Object Layer Attributes #2, Status: Stávající; Object Layer Attributes #2, Práce: Zateplovací systémy; Object Layer Attributes #2, Materiál: LIGNOPOR; Object Layer Attributes #2, Allright_Stavebni_dil_ID: 1854Ven0000000022; Object Layer Attributes #2, Jednotka: m2; Object Layer Attributes #2, Název_objektu: Věnec; Object Layer Attributes #2, Staticky nosná konstrukce: no
MINERÁLNÍ VATA | Půdorys 5.NP | YTONG 150 0.15 m, MINERÁLNÍ VATA 0.15 m |  | MINERÁLNÍ VATA |  | 1864HWa0000004725 | m3 | Celá stěna | Nový | Zednické práce | YTONG 150 | no | 1864Stě0000004726 | m2 | Stěna |  | 0.3 | 0.57 | 0.57 | 0.143 | 0.525 | 0.143 | 0.157 | 0.95 | NEMSOK - Object Layer Attributes #2, 2D interakce: yes; Object Layer Attributes #2, Status: Nový; Object Layer Attributes #2, Práce: Zateplovací systémy; Object Layer Attributes #2, Materiál: MINERÁLNÍ VATA; Object Layer Attributes #2, Allright_Stavebni_dil_ID: 1864Stě0000004727; Object Layer Attributes #2, Jednotka: m3; Object Layer Attributes #2, Název_objektu: Stěna; Object Layer Attributes #2, Staticky nosná konstrukce: no; Object Layer Attributes #1, Kód prvku: SN06.06.0002; Object Layer Attributes #1, U-hodnota: 1.111; Object Layer Attributes #1, Podlaží: 5.NP; Object Layer Attributes #1, Neprůzvučnost: 35 dB; Object Layer Attributes #1, Pevnost zdiva: 1,92 N/mm2; Object Layer Attributes #1, Funkce (venkovní): Ano; Object Layer Attributes #2, Kód prvku: TI06.06.1046; Object Layer Attributes #2, Požární odolnost: A1; Object Layer Attributes #2, Součinitel prostupu tepla: 0.036; Object Layer Attributes #2, Součinitel difúzního odporu: 1; Object Layer Attributes #2, Způsob spojení vrstev: Lepený + mechanicky kotvený; Object Layer Attributes #2, Systém kotvení: -
MINERÁLNÍ VATA | Půdorys 5.NP | YTONG 150 0.15 m, MINERÁLNÍ VATA 0.15 m |  | MINERÁLNÍ VATA |  | 1864HWa0000004706 | m3 | Celá stěna | Nový | Zednické práce | YTONG 150 | no | 1864Stě0000004707 | m2 | Stěna |  | 0.3 | 3.468 | 3.468 | 0.986 | 3.65 | 0.986 | 1.095 | 0.95 | NEMSOK - Object Layer Attributes #2, 2D interakce: yes; Object Layer Attributes #2, Status: Nový; Object Layer Attributes #2, Práce: Zateplovací systémy; Object Layer Attributes #2, Materiál: MINERÁLNÍ VATA; Object Layer Attributes #2, Allright_Stavebni_dil_ID: 1864Stě0000004708; Object Layer Attributes #2, Jednotka: m3; Object Layer Attributes #2, Název_objektu: Stěna; Object Layer Attributes #2, Staticky nosná konstrukce: no; Object Layer Attributes #1, Kód prvku: SN06.06.0001; Object Layer Attributes #1, U-hodnota: 1.111; Object Layer Attributes #1, Podlaží: 5.NP; Object Layer Attributes #1, Neprůzvučnost: 35 dB; Object Layer Attributes #1, Pevnost zdiva: 1,92 N/mm2; Object Layer Attributes #1, Funkce (venkovní): Ano; Object Layer Attributes #2, Kód prvku: TI06.06.1045; Object Layer Attributes #2, Požární odolnost: A1; Object Layer Attributes #2, Součinitel prostupu tepla: 0.036; Object Layer Attributes #2, Součinitel difúzního odporu: 1; Object Layer Attributes #2, Způsob spojení vrstev: Lepený + mechanicky kotvený; Object Layer Attributes #2, Systém kotvení: -
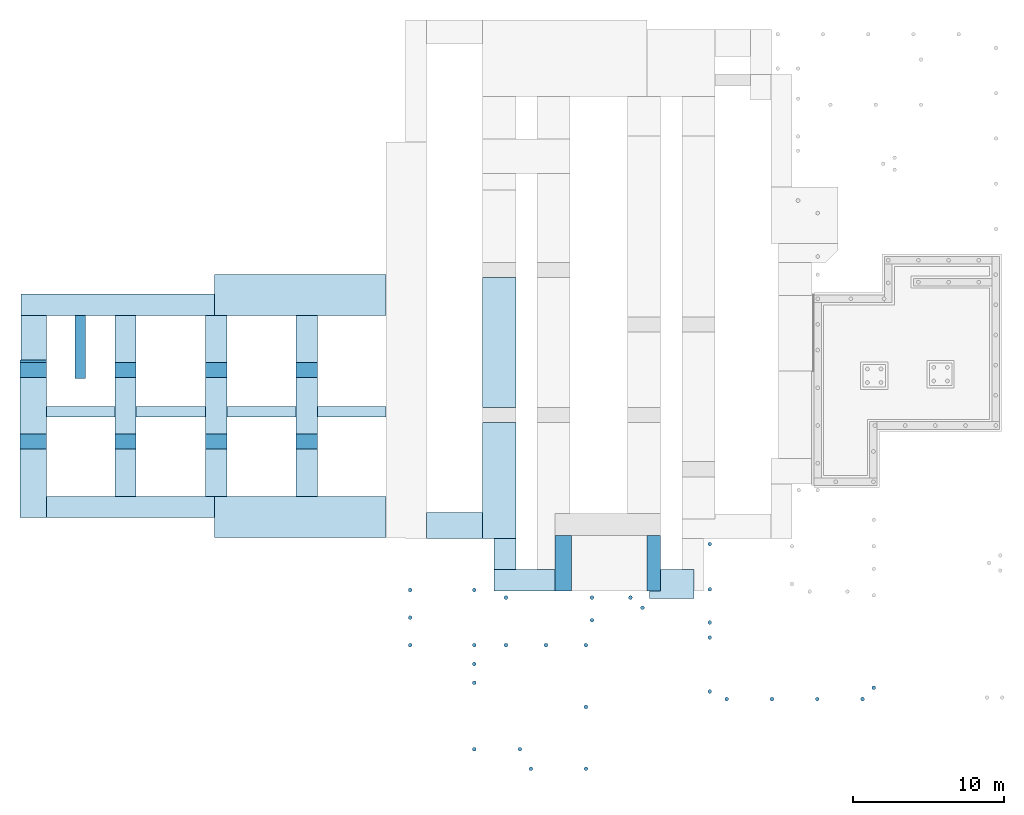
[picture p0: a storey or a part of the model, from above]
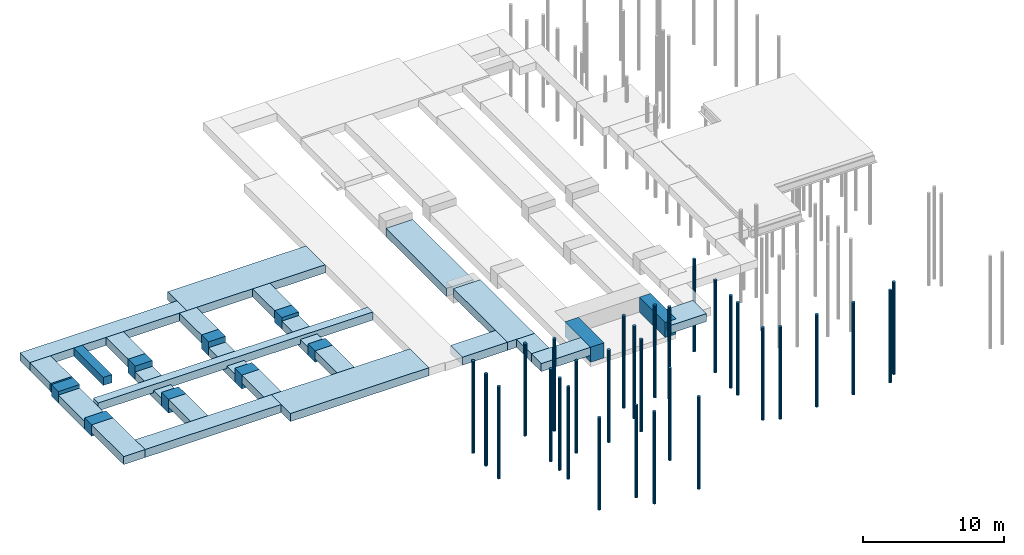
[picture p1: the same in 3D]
Properties of the parts of a building model (IFC4), part 42 of 45

# IfcWall (2385)
Name | In | Material | Faktor | Označení | Požární odolnost | Allright_Stavebni_dil_ID | Jednotka | Název_objektu | Object Layer Attributes #1, Status | Object Layer Attributes #1, Práce | Object Layer Attributes #1, Materiál | Object Layer Attributes #1, Staticky nosná konstrukce | Object Layer Attributes #1, Allright_Stavebni_dil_ID | Object Layer Attributes #1, Jednotka | Object Layer Attributes #1, Název_objektu | ThermalTransmittance (W/K/m2) | Width (m) | GrossSideArea (m2) | NetSideArea (m2) | GrossVolume (m3) | Length (m) | NetVolume (m3) | GrossFootprintArea (m2) | Height (m)
MINERÁLNÍ VATA | Půdorys 5.NP | MINERÁLNÍ VATA 0.22 m |  | MINERÁLNÍ VATA |  | 1864HWa0000000482 | m3 | Celá stěna | Nový | Zateplovací systémy | MINERÁLNÍ VATA | no | 1864Stě0000000483 | m3 | Stěna |  | 0.22 | 0.608 | 0.608 | 0.134 | 0.77 | 0.134 | 0.169 | 0.79 | NEMSOK - Object Layer Attributes #1, Kód prvku: TI06.06.1001; Object Layer Attributes #1, Požární odolnost: A1; Systém kotvení: -; Object Layer Attributes #1, Systém kotvení: -; Object Layer Attributes #1, Součinitel prostupu tepla: 0.036; Object Layer Attributes #1, Součinitel difúzního odporu: 1; Object Layer Attributes #1, Způsob spojení vrstev: Lepený + mechanicky kotvený
MINERÁLNÍ VATA | Půdorys 5.NP | MINERÁLNÍ VATA 0.22 m |  | MINERÁLNÍ VATA |  | 1864HWa0000000510 | m3 | Celá stěna | Nový | Zateplovací systémy | MINERÁLNÍ VATA | no | 1864Stě0000000511 | m3 | Stěna |  | 0.22 | 0.785 | 0.785 | 0.173 | 0.72 | 0.173 | 0.158 | 1.09 | NEMSOK - Object Layer Attributes #1, Kód prvku: TI06.06.1002; Object Layer Attributes #1, Požární odolnost: A1; Systém kotvení: -; Object Layer Attributes #1, Systém kotvení: -; Object Layer Attributes #1, Součinitel prostupu tepla: 0.036; Object Layer Attributes #1, Součinitel difúzního odporu: 1; Object Layer Attributes #1, Způsob spojení vrstev: Lepený + mechanicky kotvený
MINERÁLNÍ VATA | Půdorys 5.NP | MINERÁLNÍ VATA 0.22 m |  | MINERÁLNÍ VATA |  | 1864HWa0000000515 | m3 | Celá stěna | Nový | Zateplovací systémy | MINERÁLNÍ VATA | no | 1864Stě0000000516 | m3 | Stěna |  | 0.22 | 0.785 | 0.785 | 0.173 | 0.72 | 0.173 | 0.158 | 1.09 | NEMSOK - Object Layer Attributes #1, Kód prvku: TI06.06.1003; Object Layer Attributes #1, Požární odolnost: A1; Systém kotvení: -; Object Layer Attributes #1, Systém kotvení: -; Object Layer Attributes #1, Součinitel prostupu tepla: 0.036; Object Layer Attributes #1, Součinitel difúzního odporu: 1; Object Layer Attributes #1, Způsob spojení vrstev: Lepený + mechanicky kotvený
MINERÁLNÍ VATA | Půdorys 5.NP | MINERÁLNÍ VATA 0.22 m |  | MINERÁLNÍ VATA |  | 1864HWa0000000520 | m3 | Celá stěna | Nový | Zateplovací systémy | MINERÁLNÍ VATA | no | 1864Stě0000000521 | m3 | Stěna |  | 0.22 | 0.648 | 0.648 | 0.143 | 0.82 | 0.143 | 0.18 | 0.79 | NEMSOK - Object Layer Attributes #1, Kód prvku: TI06.06.1004; Object Layer Attributes #1, Požární odolnost: A1; Systém kotvení: -; Object Layer Attributes #1, Systém kotvení: -; Object Layer Attributes #1, Součinitel prostupu tepla: 0.036; Object Layer Attributes #1, Součinitel difúzního odporu: 1; Object Layer Attributes #1, Způsob spojení vrstev: Lepený + mechanicky kotvený
MINERÁLNÍ VATA | Půdorys 5.NP | MINERÁLNÍ VATA 0.22 m |  | MINERÁLNÍ VATA |  | 1864HWa0000000525 | m3 | Celá stěna | Nový | Zateplovací systémy | MINERÁLNÍ VATA | no | 1864Stě0000000526 | m3 | Stěna |  | 0.22 | 0.648 | 0.648 | 0.143 | 0.82 | 0.143 | 0.18 | 0.79 | NEMSOK - Object Layer Attributes #1, Kód prvku: TI06.06.1005; Object Layer Attributes #1, Požární odolnost: A1; Systém kotvení: -; Object Layer Attributes #1, Systém kotvení: -; Object Layer Attributes #1, Součinitel prostupu tepla: 0.036; Object Layer Attributes #1, Součinitel difúzního odporu: 1; Object Layer Attributes #1, Způsob spojení vrstev: Lepený + mechanicky kotvený
MINERÁLNÍ VATA | Půdorys 5.NP | MINERÁLNÍ VATA 0.22 m |  | MINERÁLNÍ VATA |  | 1864HWa0000000530 | m3 | Celá stěna | Nový | Zateplovací systémy | MINERÁLNÍ VATA | no | 1864Stě0000000531 | m3 | Stěna |  | 0.22 | 0.648 | 0.648 | 0.143 | 0.82 | 0.143 | 0.18 | 0.79 | NEMSOK - Object Layer Attributes #1, Kód prvku: TI06.06.1006; Object Layer Attributes #1, Požární odolnost: A1; Systém kotvení: -; Object Layer Attributes #1, Systém kotvení: -; Object Layer Attributes #1, Součinitel prostupu tepla: 0.036; Object Layer Attributes #1, Součinitel difúzního odporu: 1; Object Layer Attributes #1, Způsob spojení vrstev: Lepený + mechanicky kotvený
MINERÁLNÍ VATA | Půdorys 5.NP | MINERÁLNÍ VATA 0.15 m |  | MINERÁLNÍ VATA |  | 1864HWa0000000598 | m3 | Celá stěna | Nový | Zateplovací systémy | MINERÁLNÍ VATA | no | 1864Stě0000000599 | m3 | Stěna |  | 0.15 | 6.778 | 6.778 | 1.017 | 8.58 | 1.017 | 1.287 | 0.79 | NEMSOK - Object Layer Attributes #1, Kód prvku: TI06.06.1007; Object Layer Attributes #1, Požární odolnost: A1; Systém kotvení: -; Object Layer Attributes #1, Systém kotvení: -; Object Layer Attributes #1, Součinitel prostupu tepla: 0.036; Object Layer Attributes #1, Součinitel difúzního odporu: 1; Object Layer Attributes #1, Způsob spojení vrstev: Lepený + mechanicky kotvený
MINERÁLNÍ VATA | Půdorys 5.NP | MINERÁLNÍ VATA 0.15 m |  | MINERÁLNÍ VATA |  | 1864HWa0000000606 | m3 | Celá stěna | Nový | Zateplovací systémy | MINERÁLNÍ VATA | no | 1864Stě0000000607 | m3 | Stěna |  | 0.15 | 1.417 | 1.417 | 0.213 | 1.3 | 0.213 | 0.195 | 1.09 | NEMSOK - Object Layer Attributes #1, Kód prvku: TI06.06.1008; Object Layer Attributes #1, Požární odolnost: A1; Systém kotvení: -; Object Layer Attributes #1, Systém kotvení: -; Object Layer Attributes #1, Součinitel prostupu tepla: 0.036; Object Layer Attributes #1, Součinitel difúzního odporu: 1; Object Layer Attributes #1, Způsob spojení vrstev: Lepený + mechanicky kotvený
MINERÁLNÍ VATA | Půdorys 5.NP | MINERÁLNÍ VATA 0.15 m |  | MINERÁLNÍ VATA |  | 1864HWa0000000623 | m3 | Celá stěna | Nový | Zateplovací systémy | MINERÁLNÍ VATA | no | 1864Stě0000000624 | m3 | Stěna |  | 0.15 | 17.004 | 17.004 | 2.551 | 15.6 | 2.551 | 2.34 | 1.09 | NEMSOK - Object Layer Attributes #1, Kód prvku: TI06.06.1009; Object Layer Attributes #1, Požární odolnost: A1; Systém kotvení: -; Object Layer Attributes #1, Systém kotvení: -; Object Layer Attributes #1, Součinitel prostupu tepla: 0.036; Object Layer Attributes #1, Součinitel difúzního odporu: 1; Object Layer Attributes #1, Způsob spojení vrstev: Lepený + mechanicky kotvený
MINERÁLNÍ VATA | Půdorys 5.NP | MINERÁLNÍ VATA 0.15 m |  | MINERÁLNÍ VATA |  | 1864HWa0000000634 | m3 | Celá stěna | Nový | Zateplovací systémy | MINERÁLNÍ VATA | no | 1864Stě0000000635 | m3 | Stěna |  | 0.15 | 1.417 | 1.417 | 0.213 | 1.3 | 0.213 | 0.195 | 1.09 | NEMSOK - Object Layer Attributes #1, Kód prvku: TI06.06.1010; Object Layer Attributes #1, Požární odolnost: A1; Systém kotvení: -; Object Layer Attributes #1, Systém kotvení: -; Object Layer Attributes #1, Součinitel prostupu tepla: 0.036; Object Layer Attributes #1, Součinitel difúzního odporu: 1; Object Layer Attributes #1, Způsob spojení vrstev: Lepený + mechanicky kotvený
MINERÁLNÍ VATA | Půdorys 5.NP | MINERÁLNÍ VATA 0.15 m |  | MINERÁLNÍ VATA |  | 1864HWa0000000644 | m3 | Celá stěna | Nový | Zateplovací systémy | MINERÁLNÍ VATA | no | 1864Stě0000000645 | m3 | Stěna |  | 0.15 | 2.038 | 2.038 | 0.306 | 2.58 | 0.306 | 0.387 | 0.79 | NEMSOK - Object Layer Attributes #1, Kód prvku: TI06.06.1011; Object Layer Attributes #1, Požární odolnost: A1; Systém kotvení: -; Object Layer Attributes #1, Systém kotvení: -; Object Layer Attributes #1, Součinitel prostupu tepla: 0.036; Object Layer Attributes #1, Součinitel difúzního odporu: 1; Object Layer Attributes #1, Způsob spojení vrstev: Lepený + mechanicky kotvený
MINERÁLNÍ VATA | Půdorys 5.NP | MINERÁLNÍ VATA 0.15 m |  | MINERÁLNÍ VATA |  | 1864HWa0000000659 | m3 | Celá stěna | Nový | Zateplovací systémy | MINERÁLNÍ VATA | no | 1864Stě0000000660 | m3 | Stěna |  | 0.15 | 4.211 | 4.211 | 0.632 | 5.33 | 0.632 | 0.8 | 0.79 | NEMSOK - Object Layer Attributes #1, Kód prvku: TI06.06.1012; Object Layer Attributes #1, Požární odolnost: A1; Systém kotvení: -; Object Layer Attributes #1, Systém kotvení: -; Object Layer Attributes #1, Součinitel prostupu tepla: 0.036; Object Layer Attributes #1, Součinitel difúzního odporu: 1; Object Layer Attributes #1, Způsob spojení vrstev: Lepený + mechanicky kotvený
MINERÁLNÍ VATA | Půdorys 5.NP | MINERÁLNÍ VATA 0.15 m |  | MINERÁLNÍ VATA |  | 1864HWa0000000768 | m3 | Celá stěna | Nový | Zateplovací systémy | MINERÁLNÍ VATA | no | 1864Stě0000000769 | m3 | Stěna |  | 0.15 | 4.211 | 4.211 | 0.632 | 5.33 | 0.632 | 0.8 | 0.79 | NEMSOK - Object Layer Attributes #1, Kód prvku: TI06.06.1013; Object Layer Attributes #1, Požární odolnost: A1; Systém kotvení: -; Object Layer Attributes #1, Systém kotvení: -; Object Layer Attributes #1, Součinitel prostupu tepla: 0.036; Object Layer Attributes #1, Součinitel difúzního odporu: 1; Object Layer Attributes #1, Způsob spojení vrstev: Lepený + mechanicky kotvený
MINERÁLNÍ VATA | Půdorys 5.NP | MINERÁLNÍ VATA 0.15 m |  | MINERÁLNÍ VATA |  | 1864HWa0000000778 | m3 | Celá stěna | Nový | Zateplovací systémy | MINERÁLNÍ VATA | no | 1864Stě0000000779 | m3 | Stěna |  | 0.15 | 25.596 | 25.596 | 3.839 | 32.4 | 3.839 | 4.86 | 0.79 | NEMSOK - Object Layer Attributes #1, Kód prvku: TI06.06.1014; Object Layer Attributes #1, Požární odolnost: A1; Systém kotvení: -; Object Layer Attributes #1, Systém kotvení: -; Object Layer Attributes #1, Součinitel prostupu tepla: 0.036; Object Layer Attributes #1, Součinitel difúzního odporu: 1; Object Layer Attributes #1, Způsob spojení vrstev: Lepený + mechanicky kotvený
MINERÁLNÍ VATA | Půdorys 5.NP | MINERÁLNÍ VATA 0.15 m |  | MINERÁLNÍ VATA |  | 1864HWa0000000789 | m3 | Celá stěna | Nový | Zateplovací systémy | MINERÁLNÍ VATA | no | 1864Stě0000000790 | m3 | Stěna |  | 0.15 | 11.716 | 11.716 | 1.757 | 14.83 | 1.757 | 2.224 | 0.79 | NEMSOK - Object Layer Attributes #1, Kód prvku: TI06.06.1015; Object Layer Attributes #1, Požární odolnost: A1; Systém kotvení: -; Object Layer Attributes #1, Systém kotvení: -; Object Layer Attributes #1, Součinitel prostupu tepla: 0.036; Object Layer Attributes #1, Součinitel difúzního odporu: 1; Object Layer Attributes #1, Způsob spojení vrstev: Lepený + mechanicky kotvený
MINERÁLNÍ VATA | Půdorys 5.NP | MINERÁLNÍ VATA 0.15 m |  | MINERÁLNÍ VATA |  | 1864HWa0000000815 | m3 | Celá stěna | Nový | Zateplovací systémy | MINERÁLNÍ VATA | no | 1864Stě0000000816 | m3 | Stěna |  | 0.15 | 7.371 | 7.371 | 1.106 | 9.33 | 1.106 | 1.4 | 0.79 | NEMSOK - Object Layer Attributes #1, Kód prvku: TI06.06.1016; Object Layer Attributes #1, Požární odolnost: A1; Systém kotvení: -; Object Layer Attributes #1, Systém kotvení: -; Object Layer Attributes #1, Součinitel prostupu tepla: 0.036; Object Layer Attributes #1, Součinitel difúzního odporu: 1; Object Layer Attributes #1, Způsob spojení vrstev: Lepený + mechanicky kotvený
MINERÁLNÍ VATA | Půdorys 5.NP | MINERÁLNÍ VATA 0.15 m |  | MINERÁLNÍ VATA |  | 1864HWa0000000844 | m3 | Celá stěna | Nový | Zateplovací systémy | MINERÁLNÍ VATA | no | 1864Stě0000000845 | m3 | Stěna |  | 0.15 | 0.327 | 0.327 | 0.049 | 0.3 | 0.049 | 0.045 | 1.09 | NEMSOK - Object Layer Attributes #1, Kód prvku: TI06.06.1017; Object Layer Attributes #1, Požární odolnost: A1; Systém kotvení: -; Object Layer Attributes #1, Systém kotvení: -; Object Layer Attributes #1, Součinitel prostupu tepla: 0.036; Object Layer Attributes #1, Součinitel difúzního odporu: 1; Object Layer Attributes #1, Způsob spojení vrstev: Lepený + mechanicky kotvený
MINERÁLNÍ VATA | Půdorys 5.NP | MINERÁLNÍ VATA 0.15 m |  | MINERÁLNÍ VATA |  | 1864HWa0000000872 | m3 | Celá stěna | Nový | Zateplovací systémy | MINERÁLNÍ VATA | no | 1864Stě0000000873 | m3 | Stěna |  | 0.15 | 0.327 | 0.327 | 0.049 | 0.3 | 0.049 | 0.045 | 1.09 | NEMSOK - Object Layer Attributes #1, Kód prvku: TI06.06.1018; Object Layer Attributes #1, Požární odolnost: A1; Systém kotvení: -; Object Layer Attributes #1, Systém kotvení: -; Object Layer Attributes #1, Součinitel prostupu tepla: 0.036; Object Layer Attributes #1, Součinitel difúzního odporu: 1; Object Layer Attributes #1, Způsob spojení vrstev: Lepený + mechanicky kotvený
MINERÁLNÍ VATA | Půdorys 5.NP | MINERÁLNÍ VATA 0.15 m |  | MINERÁLNÍ VATA |  | 1864HWa0000002581 | m3 | Celá stěna | Nový | Zateplovací systémy | MINERÁLNÍ VATA | no | 1864Stě0000002582 | m3 | Stěna |  | 0.15 | 1.425 | 1.425 | 0.214 | 1.5 | 0.214 | 0.225 | 0.95 | NEMSOK - Object Layer Attributes #1, Kód prvku: TI06.06.1019; Object Layer Attributes #1, Požární odolnost: A1; Systém kotvení: -; Object Layer Attributes #1, Systém kotvení: -; Object Layer Attributes #1, Součinitel prostupu tepla: 0.036; Object Layer Attributes #1, Součinitel difúzního odporu: 1; Object Layer Attributes #1, Způsob spojení vrstev: Lepený + mechanicky kotvený
MINERÁLNÍ VATA | Půdorys 5.NP | MINERÁLNÍ VATA 0.15 m |  | MINERÁLNÍ VATA |  | 1864HWa0000002586 | m3 | Celá stěna | Nový | Zateplovací systémy | MINERÁLNÍ VATA | no | 1864Stě0000002587 | m3 | Stěna |  | 0.15 | 0.95 | 0.95 | 0.142 | 1 | 0.142 | 0.15 | 0.95 | NEMSOK - Object Layer Attributes #1, Kód prvku: TI06.06.1020; Object Layer Attributes #1, Požární odolnost: A1; Systém kotvení: -; Object Layer Attributes #1, Systém kotvení: -; Object Layer Attributes #1, Součinitel prostupu tepla: 0.036; Object Layer Attributes #1, Součinitel difúzního odporu: 1; Object Layer Attributes #1, Způsob spojení vrstev: Lepený + mechanicky kotvený
MINERÁLNÍ VATA | Půdorys 5.NP | MINERÁLNÍ VATA 0.15 m |  | MINERÁLNÍ VATA |  | 1864HWa0000002596 | m3 | Celá stěna | Nový | Zateplovací systémy | MINERÁLNÍ VATA | no | 1864Stě0000002597 | m3 | Stěna |  | 0.15 | 1.283 | 1.283 | 0.192 | 1.35 | 0.192 | 0.203 | 0.95 | NEMSOK - Object Layer Attributes #1, Kód prvku: TI06.06.1021; Object Layer Attributes #1, Požární odolnost: A1; Systém kotvení: -; Object Layer Attributes #1, Systém kotvení: -; Object Layer Attributes #1, Součinitel prostupu tepla: 0.036; Object Layer Attributes #1, Součinitel difúzního odporu: 1; Object Layer Attributes #1, Způsob spojení vrstev: Lepený + mechanicky kotvený
MINERÁLNÍ VATA | Půdorys 5.NP | MINERÁLNÍ VATA 0.15 m |  | MINERÁLNÍ VATA |  | 1864HWa0000002608 | m3 | Celá stěna | Nový | Zateplovací systémy | MINERÁLNÍ VATA | no | 1864Stě0000002609 | m3 | Stěna |  | 0.15 | 0.808 | 0.808 | 0.121 | 0.85 | 0.121 | 0.127 | 0.95 | NEMSOK - Object Layer Attributes #1, Kód prvku: TI06.06.1022; Object Layer Attributes #1, Požární odolnost: A1; Systém kotvení: -; Object Layer Attributes #1, Systém kotvení: -; Object Layer Attributes #1, Součinitel prostupu tepla: 0.036; Object Layer Attributes #1, Součinitel difúzního odporu: 1; Object Layer Attributes #1, Způsob spojení vrstev: Lepený + mechanicky kotvený
MINERÁLNÍ VATA | Půdorys 5.NP | MINERÁLNÍ VATA 0.15 m |  | MINERÁLNÍ VATA |  | 1864HWa0000002651 | m3 | Celá stěna | Nový | Zateplovací systémy | MINERÁLNÍ VATA | no | 1864Stě0000002652 | m3 | Stěna |  | 0.15 | 0.855 | 0.855 | 0.128 | 0.9 | 0.128 | 0.135 | 0.95 | NEMSOK - Object Layer Attributes #1, Kód prvku: TI06.06.1023; Object Layer Attributes #1, Požární odolnost: A1; Systém kotvení: -; Object Layer Attributes #1, Systém kotvení: -; Object Layer Attributes #1, Součinitel prostupu tepla: 0.036; Object Layer Attributes #1, Součinitel difúzního odporu: 1; Object Layer Attributes #1, Způsob spojení vrstev: Lepený + mechanicky kotvený
MINERÁLNÍ VATA | Půdorys 5.NP | MINERÁLNÍ VATA 0.15 m |  | MINERÁLNÍ VATA |  | 1864HWa0000002656 | m3 | Celá stěna | Nový | Zateplovací systémy | MINERÁLNÍ VATA | no | 1864Stě0000002657 | m3 | Stěna |  | 0.15 | 0.713 | 0.713 | 0.107 | 0.75 | 0.107 | 0.113 | 0.95 | NEMSOK - Object Layer Attributes #1, Kód prvku: TI06.06.1024; Object Layer Attributes #1, Požární odolnost: A1; Systém kotvení: -; Object Layer Attributes #1, Systém kotvení: -; Object Layer Attributes #1, Součinitel prostupu tepla: 0.036; Object Layer Attributes #1, Součinitel difúzního odporu: 1; Object Layer Attributes #1, Způsob spojení vrstev: Lepený + mechanicky kotvený
MINERÁLNÍ VATA | Půdorys 5.NP | MINERÁLNÍ VATA 0.15 m |  | MINERÁLNÍ VATA |  | 1864HWa0000002666 | m3 | Celá stěna | Nový | Zateplovací systémy | MINERÁLNÍ VATA | no | 1864Stě0000002667 | m3 | Stěna |  | 0.15 | 0.713 | 0.713 | 0.107 | 0.75 | 0.107 | 0.113 | 0.95 | NEMSOK - Object Layer Attributes #1, Kód prvku: TI06.06.1025; Object Layer Attributes #1, Požární odolnost: A1; Systém kotvení: -; Object Layer Attributes #1, Systém kotvení: -; Object Layer Attributes #1, Součinitel prostupu tepla: 0.036; Object Layer Attributes #1, Součinitel difúzního odporu: 1; Object Layer Attributes #1, Způsob spojení vrstev: Lepený + mechanicky kotvený
MINERÁLNÍ VATA | Půdorys 5.NP | MINERÁLNÍ VATA 0.15 m |  | MINERÁLNÍ VATA |  | 1864HWa0000002678 | m3 | Celá stěna | Nový | Zateplovací systémy | MINERÁLNÍ VATA | no | 1864Stě0000002679 | m3 | Stěna |  | 0.15 | 0.57 | 0.57 | 0.086 | 0.6 | 0.086 | 0.09 | 0.95 | NEMSOK - Object Layer Attributes #1, Kód prvku: TI06.06.1026; Object Layer Attributes #1, Požární odolnost: A1; Systém kotvení: -; Object Layer Attributes #1, Systém kotvení: -; Object Layer Attributes #1, Součinitel prostupu tepla: 0.036; Object Layer Attributes #1, Součinitel difúzního odporu: 1; Object Layer Attributes #1, Způsob spojení vrstev: Lepený + mechanicky kotvený
MINERÁLNÍ VATA | Půdorys 5.NP | MINERÁLNÍ VATA 0.15 m |  | MINERÁLNÍ VATA |  | 1864HWa0000002695 | m3 | Celá stěna | Nový | Zateplovací systémy | MINERÁLNÍ VATA | no | 1864Stě0000002696 | m3 | Stěna |  | 0.15 | 0.855 | 0.855 | 0.128 | 0.9 | 0.128 | 0.135 | 0.95 | NEMSOK - Object Layer Attributes #1, Kód prvku: TI06.06.1027; Object Layer Attributes #1, Požární odolnost: A1; Systém kotvení: -; Object Layer Attributes #1, Systém kotvení: -; Object Layer Attributes #1, Součinitel prostupu tepla: 0.036; Object Layer Attributes #1, Součinitel difúzního odporu: 1; Object Layer Attributes #1, Způsob spojení vrstev: Lepený + mechanicky kotvený
MINERÁLNÍ VATA | Půdorys 5.NP | MINERÁLNÍ VATA 0.15 m |  | MINERÁLNÍ VATA |  | 1864HWa0000002700 | m3 | Celá stěna | Nový | Zateplovací systémy | MINERÁLNÍ VATA | no | 1864Stě0000002701 | m3 | Stěna |  | 0.15 | 0.713 | 0.713 | 0.107 | 0.75 | 0.107 | 0.113 | 0.95 | NEMSOK - Object Layer Attributes #1, Kód prvku: TI06.06.1028; Object Layer Attributes #1, Požární odolnost: A1; Systém kotvení: -; Object Layer Attributes #1, Systém kotvení: -; Object Layer Attributes #1, Součinitel prostupu tepla: 0.036; Object Layer Attributes #1, Součinitel difúzního odporu: 1; Object Layer Attributes #1, Způsob spojení vrstev: Lepený + mechanicky kotvený
MINERÁLNÍ VATA | Půdorys 5.NP | MINERÁLNÍ VATA 0.15 m |  | MINERÁLNÍ VATA |  | 1864HWa0000002710 | m3 | Celá stěna | Nový | Zateplovací systémy | MINERÁLNÍ VATA | no | 1864Stě0000002711 | m3 | Stěna |  | 0.15 | 0.713 | 0.713 | 0.107 | 0.75 | 0.107 | 0.113 | 0.95 | NEMSOK - Object Layer Attributes #1, Kód prvku: TI06.06.1029; Object Layer Attributes #1, Požární odolnost: A1; Systém kotvení: -; Object Layer Attributes #1, Systém kotvení: -; Object Layer Attributes #1, Součinitel prostupu tepla: 0.036; Object Layer Attributes #1, Součinitel difúzního odporu: 1; Object Layer Attributes #1, Způsob spojení vrstev: Lepený + mechanicky kotvený
MINERÁLNÍ VATA | Půdorys 5.NP | MINERÁLNÍ VATA 0.15 m |  | MINERÁLNÍ VATA |  | 1864HWa0000002722 | m3 | Celá stěna | Nový | Zateplovací systémy | MINERÁLNÍ VATA | no | 1864Stě0000002723 | m3 | Stěna |  | 0.15 | 0.57 | 0.57 | 0.086 | 0.6 | 0.086 | 0.09 | 0.95 | NEMSOK - Object Layer Attributes #1, Kód prvku: TI06.06.1030; Object Layer Attributes #1, Požární odolnost: A1; Systém kotvení: -; Object Layer Attributes #1, Systém kotvení: -; Object Layer Attributes #1, Součinitel prostupu tepla: 0.036; Object Layer Attributes #1, Součinitel difúzního odporu: 1; Object Layer Attributes #1, Způsob spojení vrstev: Lepený + mechanicky kotvený
MINERÁLNÍ VATA | Půdorys 5.NP | MINERÁLNÍ VATA 0.15 m |  | MINERÁLNÍ VATA |  | 1864HWa0000002739 | m3 | Celá stěna | Nový | Zateplovací systémy | MINERÁLNÍ VATA | no | 1864Stě0000002740 | m3 | Stěna |  | 0.15 | 0.732 | 0.732 | 0.11 | 0.77 | 0.11 | 0.116 | 0.95 | NEMSOK - Object Layer Attributes #1, Kód prvku: TI06.06.1031; Object Layer Attributes #1, Požární odolnost: A1; Systém kotvení: -; Object Layer Attributes #1, Systém kotvení: -; Object Layer Attributes #1, Součinitel prostupu tepla: 0.036; Object Layer Attributes #1, Součinitel difúzního odporu: 1; Object Layer Attributes #1, Způsob spojení vrstev: Lepený + mechanicky kotvený
MINERÁLNÍ VATA | Půdorys 5.NP | MINERÁLNÍ VATA 0.15 m |  | MINERÁLNÍ VATA |  | 1864HWa0000002744 | m3 | Celá stěna | Nový | Zateplovací systémy | MINERÁLNÍ VATA | no | 1864Stě0000002745 | m3 | Stěna |  | 0.15 | 0.713 | 0.713 | 0.107 | 0.75 | 0.107 | 0.113 | 0.95 | NEMSOK - Object Layer Attributes #1, Kód prvku: TI06.06.1032; Object Layer Attributes #1, Požární odolnost: A1; Systém kotvení: -; Object Layer Attributes #1, Systém kotvení: -; Object Layer Attributes #1, Součinitel prostupu tepla: 0.036; Object Layer Attributes #1, Součinitel difúzního odporu: 1; Object Layer Attributes #1, Způsob spojení vrstev: Lepený + mechanicky kotvený
MINERÁLNÍ VATA | Půdorys 5.NP | MINERÁLNÍ VATA 0.15 m |  | MINERÁLNÍ VATA |  | 1864HWa0000002754 | m3 | Celá stěna | Nový | Zateplovací systémy | MINERÁLNÍ VATA | no | 1864Stě0000002755 | m3 | Stěna |  | 0.15 | 0.589 | 0.589 | 0.088 | 0.62 | 0.088 | 0.093 | 0.95 | NEMSOK - Object Layer Attributes #1, Kód prvku: TI06.06.1033; Object Layer Attributes #1, Požární odolnost: A1; Systém kotvení: -; Object Layer Attributes #1, Systém kotvení: -; Object Layer Attributes #1, Součinitel prostupu tepla: 0.036; Object Layer Attributes #1, Součinitel difúzního odporu: 1; Object Layer Attributes #1, Způsob spojení vrstev: Lepený + mechanicky kotvený
MINERÁLNÍ VATA | Půdorys 5.NP | MINERÁLNÍ VATA 0.15 m |  | MINERÁLNÍ VATA |  | 1864HWa0000003817 | m3 | Celá stěna | Nový | Zateplovací systémy | MINERÁLNÍ VATA | no | 1864Stě0000003818 | m3 | Stěna |  | 0.15 | 0.114 | 0.114 | 0.017 | 0.6 | 0.017 | 0.09 | 0.19 | NEMSOK - Object Layer Attributes #1, Kód prvku: TI06.06.1034; Object Layer Attributes #1, Požární odolnost: A1; Systém kotvení: -; Object Layer Attributes #1, Systém kotvení: -; Object Layer Attributes #1, Součinitel prostupu tepla: 0.036; Object Layer Attributes #1, Součinitel difúzního odporu: 1; Object Layer Attributes #1, Způsob spojení vrstev: Lepený + mechanicky kotvený
MINERÁLNÍ VATA | Půdorys 5.NP | MINERÁLNÍ VATA 0.15 m |  | MINERÁLNÍ VATA |  | 1864HWa0000003822 | m3 | Celá stěna | Nový | Zateplovací systémy | MINERÁLNÍ VATA | no | 1864Stě0000003823 | m3 | Stěna |  | 0.15 | 0.143 | 0.143 | 0.021 | 0.75 | 0.021 | 0.113 | 0.19 | NEMSOK - Object Layer Attributes #1, Kód prvku: TI06.06.1035; Object Layer Attributes #1, Požární odolnost: A1; Systém kotvení: -; Object Layer Attributes #1, Systém kotvení: -; Object Layer Attributes #1, Součinitel prostupu tepla: 0.036; Object Layer Attributes #1, Součinitel difúzního odporu: 1; Object Layer Attributes #1, Způsob spojení vrstev: Lepený + mechanicky kotvený
MINERÁLNÍ VATA | Půdorys 5.NP | MINERÁLNÍ VATA 0.15 m |  | MINERÁLNÍ VATA |  | 1864HWa0000003832 | m3 | Celá stěna | Nový | Zateplovací systémy | MINERÁLNÍ VATA | no | 1864Stě0000003833 | m3 | Stěna |  | 0.15 | 0.085 | 0.086 | 0.013 | 0.45 | 0.013 | 0.067 | 0.19 | NEMSOK - Object Layer Attributes #1, Kód prvku: TI06.06.1036; Object Layer Attributes #1, Požární odolnost: A1; Systém kotvení: -; Object Layer Attributes #1, Systém kotvení: -; Object Layer Attributes #1, Součinitel prostupu tepla: 0.036; Object Layer Attributes #1, Součinitel difúzního odporu: 1; Object Layer Attributes #1, Způsob spojení vrstev: Lepený + mechanicky kotvený
MINERÁLNÍ VATA | Půdorys 5.NP | MINERÁLNÍ VATA 0.15 m |  | MINERÁLNÍ VATA |  | 1864HWa0000003865 | m3 | Celá stěna | Nový | Zateplovací systémy | MINERÁLNÍ VATA | no | 1864Stě0000003867 | m3 | Stěna |  | 0.15 | 1.449 | 1.449 | 0.217 | 2.1 | 0.217 | 0.315 | 0.69 | NEMSOK - Object Layer Attributes #1, Kód prvku: TI06.06.1037; Object Layer Attributes #1, Požární odolnost: A1; Systém kotvení: -; Object Layer Attributes #1, Systém kotvení: -; Object Layer Attributes #1, Součinitel prostupu tepla: 0.036; Object Layer Attributes #1, Součinitel difúzního odporu: 1; Object Layer Attributes #1, Způsob spojení vrstev: Lepený + mechanicky kotvený
MINERÁLNÍ VATA | Půdorys 5.NP | MINERÁLNÍ VATA 0.15 m |  | MINERÁLNÍ VATA |  | 1864HWa0000003892 | m3 | Celá stěna | Nový | Zateplovací systémy | MINERÁLNÍ VATA | no | 1864Stě0000003894 | m3 | Stěna |  | 0.15 | 5.198 | 5.198 | 0.78 | 3.6 | 0.78 | 0.54 | 1.444 | NEMSOK - Object Layer Attributes #1, Kód prvku: TI06.06.1038; Object Layer Attributes #1, Požární odolnost: A1; Systém kotvení: -; Object Layer Attributes #1, Systém kotvení: -; Object Layer Attributes #1, Součinitel prostupu tepla: 0.036; Object Layer Attributes #1, Součinitel difúzního odporu: 1; Object Layer Attributes #1, Způsob spojení vrstev: Lepený + mechanicky kotvený
MINERÁLNÍ VATA | Půdorys 5.NP | MINERÁLNÍ VATA 0.15 m |  | MINERÁLNÍ VATA |  | 1864HWa0000003899 | m3 | Celá stěna | Nový | Zateplovací systémy | MINERÁLNÍ VATA | no | 1864Stě0000003901 | m3 | Stěna |  | 0.15 | 5.153 | 5.153 | 0.773 | 2.25 | 0.773 | 0.338 | 2.29 | NEMSOK - Object Layer Attributes #1, Kód prvku: TI06.06.1039; Object Layer Attributes #1, Požární odolnost: A1; Systém kotvení: -; Object Layer Attributes #1, Systém kotvení: -; Object Layer Attributes #1, Součinitel prostupu tepla: 0.036; Object Layer Attributes #1, Součinitel difúzního odporu: 1; Object Layer Attributes #1, Způsob spojení vrstev: Lepený + mechanicky kotvený
MINERÁLNÍ VATA | Půdorys 5.NP | MINERÁLNÍ VATA 0.15 m |  | MINERÁLNÍ VATA |  | 1864HWa0000003966 | m3 | Celá stěna | Nový | Zateplovací systémy | MINERÁLNÍ VATA | no | 1864Stě0000003967 | m3 | Stěna |  | 0.15 | 5.404 | 5.404 | 0.811 | 2.36 | 0.811 | 0.354 | 2.29 | NEMSOK - Object Layer Attributes #1, Kód prvku: TI06.06.1040; Object Layer Attributes #1, Požární odolnost: A1; Systém kotvení: -; Object Layer Attributes #1, Systém kotvení: -; Object Layer Attributes #1, Součinitel prostupu tepla: 0.036; Object Layer Attributes #1, Součinitel difúzního odporu: 1; Object Layer Attributes #1, Způsob spojení vrstev: Lepený + mechanicky kotvený
MINERÁLNÍ VATA | Půdorys 5.NP | MINERÁLNÍ VATA 0.15 m |  | MINERÁLNÍ VATA |  | 1864HWa0000004172 | m3 | Celá stěna | Nový | Zateplovací systémy | MINERÁLNÍ VATA | no | 1864Stě0000004173 | m3 | Stěna |  | 0.15 | 1.628 | 1.628 | 0.244 | 2.36 | 0.244 | 0.354 | 0.69 | NEMSOK - Object Layer Attributes #1, Kód prvku: TI06.06.1041; Object Layer Attributes #1, Požární odolnost: A1; Systém kotvení: -; Object Layer Attributes #1, Systém kotvení: -; Object Layer Attributes #1, Součinitel prostupu tepla: 0.036; Object Layer Attributes #1, Součinitel difúzního odporu: 1; Object Layer Attributes #1, Způsob spojení vrstev: Lepený + mechanicky kotvený
MINERÁLNÍ VATA | Půdorys 5.NP | MINERÁLNÍ VATA 0.22 m |  | MINERÁLNÍ VATA |  | 1864HWa0000004418 | m3 | Celá stěna | Nový | Zateplovací systémy | MINERÁLNÍ VATA | no | 1864Stě0000004424 | m3 | Stěna |  | 0.22 | 1.449 | 1.449 | 0.319 | 2.1 | 0.319 | 0.462 | 0.69 | NEMSOK - Object Layer Attributes #1, Kód prvku: TI06.06.1042; Object Layer Attributes #1, Požární odolnost: A1; Systém kotvení: -; Object Layer Attributes #1, Systém kotvení: -; Object Layer Attributes #1, Součinitel prostupu tepla: 0.036; Object Layer Attributes #1, Součinitel difúzního odporu: 1; Object Layer Attributes #1, Způsob spojení vrstev: Lepený + mechanicky kotvený
MINERÁLNÍ VATA | Půdorys 5.NP | MINERÁLNÍ VATA 0.22 m |  | MINERÁLNÍ VATA |  | 1864HWa0000004420 | m3 | Celá stěna | Nový | Zateplovací systémy | MINERÁLNÍ VATA | no | 1864Stě0000004425 | m3 | Stěna |  | 0.22 | 5.153 | 5.153 | 1.134 | 2.25 | 1.134 | 0.495 | 2.29 | NEMSOK - Object Layer Attributes #1, Kód prvku: TI06.06.1043; Object Layer Attributes #1, Požární odolnost: A1; Systém kotvení: -; Object Layer Attributes #1, Systém kotvení: -; Object Layer Attributes #1, Součinitel prostupu tepla: 0.036; Object Layer Attributes #1, Součinitel difúzního odporu: 1; Object Layer Attributes #1, Způsob spojení vrstev: Lepený + mechanicky kotvený
MINERÁLNÍ VATA | Půdorys 5.NP | MINERÁLNÍ VATA 0.22 m |  | MINERÁLNÍ VATA |  | 1864HWa0000004422 | m3 | Celá stěna | Nový | Zateplovací systémy | MINERÁLNÍ VATA | no | 1864Stě0000004426 | m3 | Stěna |  | 0.22 | 5.198 | 5.198 | 1.144 | 3.6 | 1.144 | 0.792 | 1.444 | NEMSOK - Object Layer Attributes #1, Kód prvku: TI06.06.1044; Object Layer Attributes #1, Požární odolnost: A1; Systém kotvení: -; Object Layer Attributes #1, Systém kotvení: -; Object Layer Attributes #1, Součinitel prostupu tepla: 0.036; Object Layer Attributes #1, Součinitel difúzního odporu: 1; Object Layer Attributes #1, Způsob spojení vrstev: Lepený + mechanicky kotvený
ZDIVO Z CDm | Půdorys 6.NP | EPS 0.1 m, PLYNOSILIKÁT 0.3 m | 1 | ZDIVO Z CDm | A | 1952HWa0000000033 | m3 | Celá stěna | Stávající | Zateplovací systémy | EPS | no | 1952Stě0000000034 | m2 | Stěna | 0 | 0.4 | 31.468 | 31.169 | 12.188 | 9.25 | 12.068 | 3.66 | 3.33 | NEMSOK - Object Layer Attributes #2, 2D interakce: yes; Object Layer Attributes #2, Status: Stávající; Object Layer Attributes #2, Práce: Zednické práce; Object Layer Attributes #2, Materiál: PLYNOSILIKÁT; Object Layer Attributes #2, Allright_Stavebni_dil_ID: 1952Stě0798426988; Object Layer Attributes #2, Jednotka: m3; Object Layer Attributes #2, Název_objektu: Stěna; Object Layer Attributes #2, Staticky nosná konstrukce: no
ZDIVO Z CDm | Půdorys 6.NP | PLYNOSILIKÁT |  | ZDIVO Z CDm | A | 1952HWa0798427132 | m3 | Celá stěna | Stávající | Zednické práce | PLYNOSILIKÁT | no | 1952Stě0798427154 | m3 | Stěna | 0 | 0.3 | 27.472 | 25.108 | 8.242 | 8.25 | 7.614 | 2.475 | 3.33
ZDIVO Z CDm | Půdorys 6.NP | EPS 0.1 m, PLYNOSILIKÁT 0.3 m |  | ZDIVO Z CDm | A | 1952HWa0000000066 | m3 | Celá stěna | Stávající | Zateplovací systémy | EPS | no | 1952Stě0000000067 | m2 | Stěna | 0 | 0.4 | 14.22 | 14.22 | 5.688 | 3.6 | 5.688 | 1.44 | 3.95 | NEMSOK - Object Layer Attributes #2, 2D interakce: yes; Object Layer Attributes #2, Status: Stávající; Object Layer Attributes #2, Práce: Zednické práce; Object Layer Attributes #2, Materiál: PLYNOSILIKÁT; Object Layer Attributes #2, Allright_Stavebni_dil_ID: 1952Stě0798427229; Object Layer Attributes #2, Jednotka: m3; Object Layer Attributes #2, Název_objektu: Stěna; Object Layer Attributes #2, Staticky nosná konstrukce: no
ZDIVO Z CDm | Půdorys 6.NP | EPS 0.1 m, PLYNOSILIKÁT 0.3 m | 1 | ZDIVO Z CDm | A | 1952HWa0000000017 | m3 | Celá stěna | Stávající | Zateplovací systémy | EPS | no | 1952Stě0000000018 | m2 | Stěna | 0 | 0.4 | 34.167 | 34.168 | 13.193 | 8.45 | 13.193 | 3.34 | 3.95 | NEMSOK - Object Layer Attributes #2, 2D interakce: yes; Object Layer Attributes #2, Status: Stávající; Object Layer Attributes #2, Práce: Zednické práce; Object Layer Attributes #2, Materiál: PLYNOSILIKÁT; Object Layer Attributes #2, Allright_Stavebni_dil_ID: 1952Stě0798427289; Object Layer Attributes #2, Jednotka: m3; Object Layer Attributes #2, Název_objektu: Stěna; Object Layer Attributes #2, Staticky nosná konstrukce: no
ZDIVO Z CDm | Půdorys 6.NP | EPS 0.1 m, PLYNOSILIKÁT 0.3 m | 1 | ZDIVO Z CDm | A | 1952HWa0000000022 | m3 | Celá stěna | Stávající | Zateplovací systémy | EPS | no | 1952Stě0000000023 | m2 | Stěna | 0 | 0.4 | 14.22 | 14.22 | 5.333 | 3.45 | 5.333 | 1.35 | 3.95 | NEMSOK - Object Layer Attributes #2, 2D interakce: yes; Object Layer Attributes #2, Status: Stávající; Object Layer Attributes #2, Práce: Zednické práce; Object Layer Attributes #2, Materiál: PLYNOSILIKÁT; Object Layer Attributes #2, Allright_Stavebni_dil_ID: 1952Stě0798427325; Object Layer Attributes #2, Jednotka: m3; Object Layer Attributes #2, Název_objektu: Stěna; Object Layer Attributes #2, Staticky nosná konstrukce: no
ZDIVO Z CDm | Půdorys 6.NP | EPS 0.1 m, PLYNOSILIKÁT 0.3 m | 1 | ZDIVO Z CDm | A | 1952HWa0000001066 | m3 | Celá stěna | Stávající | Zateplovací systémy | EPS | no | 1952Stě0000001081 | m2 | Stěna | 0 | 0.4 | 22.977 | 17.598 | 8.891 | 6.75 | 7.031 | 2.67 | 3.33 | NEMSOK - Object Layer Attributes #2, 2D interakce: yes; Object Layer Attributes #2, Status: Stávající; Object Layer Attributes #2, Práce: Zednické práce; Object Layer Attributes #2, Materiál: PLYNOSILIKÁT; Object Layer Attributes #2, Allright_Stavebni_dil_ID: 1952Stě0798427369; Object Layer Attributes #2, Jednotka: m3; Object Layer Attributes #2, Název_objektu: Stěna; Object Layer Attributes #2, Staticky nosná konstrukce: no
ZDIVO Z CDm | Půdorys 6.NP | EPS 0.1 m, PLYNOSILIKÁT 0.3 m |  | ZDIVO Z CDm | A | 1952HWa0000000055 | m3 | Celá stěna | Stávající | Zateplovací systémy | EPS | no | 1952Stě0000000056 | m2 | Stěna | 0 | 0.4 | 3.064 | 3.064 | 0.806 | 0.65 | 0.806 | 0.23 | 3.83 | NEMSOK - Object Layer Attributes #2, 2D interakce: yes; Object Layer Attributes #2, Status: Stávající; Object Layer Attributes #2, Práce: Zednické práce; Object Layer Attributes #2, Materiál: PLYNOSILIKÁT; Object Layer Attributes #2, Allright_Stavebni_dil_ID: 1952Stě0798427190; Object Layer Attributes #2, Jednotka: m3; Object Layer Attributes #2, Název_objektu: Stěna; Object Layer Attributes #2, Staticky nosná konstrukce: no
ZDIVO Z CDm | Půdorys 6.NP | EPS 0.1 m, PLYNOSILIKÁT 0.3 m |  | ZDIVO Z CDm | A | 1952HWa0000000044 | m3 | Celá stěna | Stávající | Zateplovací systémy | EPS | no | 1952Stě0000000045 | m2 | Stěna | 0 | 0.4 | 27.193 | 27.193 | 9.612 | 7 | 9.612 | 2.78 | 3.83 | NEMSOK - Object Layer Attributes #2, 2D interakce: yes; Object Layer Attributes #2, Status: Stávající; Object Layer Attributes #2, Práce: Zednické práce; Object Layer Attributes #2, Materiál: PLYNOSILIKÁT; Object Layer Attributes #2, Allright_Stavebni_dil_ID: 1952Stě0798426947; Object Layer Attributes #2, Jednotka: m3; Object Layer Attributes #2, Název_objektu: Stěna; Object Layer Attributes #2, Staticky nosná konstrukce: no
ZDIVO Z CDm | Půdorys 6.NP | ZDIVO Z CDm 0.15 m |  | ZDIVO Z CDm | A | 1952HWa0000002319 | m3 | Celá stěna | Stávající | Zednické práce | ZDIVO Z CDm |  | 1952Stě0000002320 | m3 | Stěna | 0 | 0.15 | 1.155 | 1.155 | 0.173 | 1.05 | 0.173 | 0.158 | 1.1
ZDIVO Z CDm | Půdorys 6.NP | ZDIVO Z CDm 0.15 m |  | ZDIVO Z CDm | A | 1952HWa0000002329 | m3 | Celá stěna | Stávající | Zednické práce | ZDIVO Z CDm |  | 1952Stě0000002330 | m3 | Stěna | 0 | 0.15 | 0.495 | 0.495 | 0.074 | 0.45 | 0.074 | 0.068 | 1.1
ZDIVO Z CDm | Půdorys 6.NP | ZDIVO Z CDm 0.15 m |  | ZDIVO Z CDm | A | 1952HWa0000002341 | m3 | Celá stěna | Stávající | Zednické práce | ZDIVO Z CDm |  | 1952Stě0000002342 | m3 | Stěna | 0 | 0.15 | 0.99 | 0.99 | 0.149 | 0.9 | 0.149 | 0.135 | 1.1
ZDIVO Z CDm | Půdorys 6.NP | ZDIVO Z CDm 0.15 m |  | ZDIVO Z CDm | A | 1952HWa0000002314 | m3 | Celá stěna | Stávající | Zednické práce | ZDIVO Z CDm |  | 1952Stě0000002315 | m3 | Stěna | 0 | 0.15 | 0.66 | 0.66 | 0.099 | 0.6 | 0.099 | 0.09 | 1.1
ZELEZOBETONOVÁ KCE | Půdorys 6.NP | EPS 0.05 m, ZELEZOBETONOVÁ KCE 0.32 m |  | ZELEZOBETONOVÁ KCE | A | 1952HWa0000002292 | m3 | Celá stěna | Stávající | Zateplovací systémy | EPS | no | 1952Stě0000002293 | m2 | Stěna | 0 | 0.37 | 19.575 | 19.282 | 7.079 | 15.98 | 6.971 | 5.826 | 1.25 | NEMSOK - Object Layer Attributes #2, 2D interakce: yes; Object Layer Attributes #2, Status: Stávající; Object Layer Attributes #2, Práce: Betonářské práce; Object Layer Attributes #2, Materiál: ZELEZOBETONOVÁ KCE; Object Layer Attributes #2, Allright_Stavebni_dil_ID: 1952Stě0798426176; Object Layer Attributes #2, Jednotka: m3; Object Layer Attributes #2, Název_objektu: Stěna; Object Layer Attributes #2, Staticky nosná konstrukce: no
ZDIVO Z CDm | Půdorys 6.NP | EPS 0.05 m, ZDIVO Z CDm 0.32 m |  | ZDIVO Z CDm | A | 1952HWa0000002281 | m3 | Celá stěna | Stávající | Zateplovací systémy | EPS | no | 1952Stě0000002282 | m2 | Stěna | 0 | 0.37 | 1 | 1 | 0.354 | 0.975 | 0.354 | 0.354 | 1 | NEMSOK - Object Layer Attributes #2, 2D interakce: yes; Object Layer Attributes #2, Status: Stávající; Object Layer Attributes #2, Práce: Zednické práce; Object Layer Attributes #2, Materiál: ZDIVO Z CDm; Object Layer Attributes #2, Allright_Stavebni_dil_ID: 1952Stě0798426119; Object Layer Attributes #2, Jednotka: m3; Object Layer Attributes #2, Název_objektu: Stěna; Object Layer Attributes #2, Staticky nosná konstrukce: no
ZELEZOBETONOVÁ KCE | Půdorys 6.NP | EPS 0.05 m, ZELEZOBETONOVÁ KCE 0.32 m |  | ZELEZOBETONOVÁ KCE | A | 1952HWa0000002307 | m3 | Celá stěna | Stávající | Zateplovací systémy | EPS | no | 1952Stě0000002308 | m2 | Stěna | 0 | 0.37 | 12 | 11.82 | 4.32 | 9.6 | 4.253 | 3.552 | 1.25 | NEMSOK - Object Layer Attributes #2, 2D interakce: yes; Object Layer Attributes #2, Status: Stávající; Object Layer Attributes #2, Práce: Betonářské práce; Object Layer Attributes #2, Materiál: ZELEZOBETONOVÁ KCE; Object Layer Attributes #2, Allright_Stavebni_dil_ID: 1952Stě0798426219; Object Layer Attributes #2, Jednotka: m3; Object Layer Attributes #2, Název_objektu: Stěna; Object Layer Attributes #2, Staticky nosná konstrukce: no
ZDIVO Z CDm | Půdorys 6.NP | EPS 0.05 m, ZDIVO Z CDm 0.32 m |  | ZDIVO Z CDm | A | 1952HWa0000002263 | m3 | Celá stěna | Stávající | Zateplovací systémy | EPS | no | 1952Stě0000002264 | m2 | Stěna | 0 | 0.37 | 1 | 1 | 0.354 | 0.975 | 0.354 | 0.354 | 1 | NEMSOK - Object Layer Attributes #2, 2D interakce: yes; Object Layer Attributes #2, Status: Stávající; Object Layer Attributes #2, Práce: Zednické práce; Object Layer Attributes #2, Materiál: ZDIVO Z CDm; Object Layer Attributes #2, Allright_Stavebni_dil_ID: 1952Stě0798426269; Object Layer Attributes #2, Jednotka: m3; Object Layer Attributes #2, Název_objektu: Stěna; Object Layer Attributes #2, Staticky nosná konstrukce: no
ZDIVO Z CDm | Půdorys 6.NP | EPS 0.05 m, ZDIVO Z CDm 0.3 m |  | ZDIVO Z CDm | A | 1952HWa0000002157 | m3 | Celá stěna | Stávající | Zateplovací systémy | EPS | no | 1952Stě0000002158 | m2 | Stěna | 0 | 0.35 | 1.15 | 1.15 | 0.397 | 1.14 | 0.397 | 0.397 | 1 | NEMSOK - Object Layer Attributes #2, 2D interakce: yes; Object Layer Attributes #2, Status: Stávající; Object Layer Attributes #2, Práce: Zednické práce; Object Layer Attributes #2, Materiál: ZDIVO Z CDm; Object Layer Attributes #2, Allright_Stavebni_dil_ID: 1952Stě0798426300; Object Layer Attributes #2, Jednotka: m3; Object Layer Attributes #2, Název_objektu: Stěna; Object Layer Attributes #2, Staticky nosná konstrukce: no
ZDIVO Z CDm | Půdorys 6.NP | EPS 0.05 m, ZDIVO Z CDm 0.3 m |  | ZDIVO Z CDm | A | 1952HWa0000002162 | m3 | Celá stěna | Stávající | Zateplovací systémy | EPS | no | 1952Stě0000002163 | m2 | Stěna | 0 | 0.35 | 3.67 | 3.58 | 1.282 | 3.645 | 1.25 | 1.282 | 1 | NEMSOK - Object Layer Attributes #2, 2D interakce: yes; Object Layer Attributes #2, Status: Stávající; Object Layer Attributes #2, Práce: Zednické práce; Object Layer Attributes #2, Materiál: ZDIVO Z CDm; Object Layer Attributes #2, Allright_Stavebni_dil_ID: 1952Stě0798426425; Object Layer Attributes #2, Jednotka: m3; Object Layer Attributes #2, Název_objektu: Stěna; Object Layer Attributes #2, Staticky nosná konstrukce: no
ZDIVO Z CDm | Půdorys 6.NP | EPS 0.15 m, ZDIVO Z CDm 0.3 m |  | ZDIVO Z CDm | A | 1952HWa0798426793 | m3 | Celá stěna | Stávající | Zateplovací systémy | EPS | no | 1952Stě0798426795 | m2 | Stěna | 0 | 0.45 | 10.96 | 10.712 | 4.932 | 10.96 | 4.821 | 4.932 | 1 | NEMSOK - Object Layer Attributes #2, 2D interakce: yes; Object Layer Attributes #2, Status: Stávající; Object Layer Attributes #2, Práce: Zednické práce; Object Layer Attributes #2, Materiál: ZDIVO Z CDm; Object Layer Attributes #2, Allright_Stavebni_dil_ID: 1952Stě0798426902; Object Layer Attributes #2, Jednotka: m3; Object Layer Attributes #2, Název_objektu: Stěna; Object Layer Attributes #2, Staticky nosná konstrukce: no
ZDIVO Z CDm | Půdorys 6.NP | EPS 0.1 m, ZDIVO Z CDm 0.3 m |  | ZDIVO Z CDm | A | 1952HWa0798426770 | m3 | Celá stěna | Stávající | Zateplovací systémy | EPS | no | 1952Stě0798426772 | m2 | Stěna | 0 | 0.4 | 1.24 | 1.24 | 0.406 | 1.09 | 0.406 | 0.406 | 1 | NEMSOK - Object Layer Attributes #2, 2D interakce: yes; Object Layer Attributes #2, Status: Stávající; Object Layer Attributes #2, Práce: Zednické práce; Object Layer Attributes #2, Materiál: ZDIVO Z CDm; Object Layer Attributes #2, Allright_Stavebni_dil_ID: 1952Stě0798426857; Object Layer Attributes #2, Jednotka: m3; Object Layer Attributes #2, Název_objektu: Stěna; Object Layer Attributes #2, Staticky nosná konstrukce: no
ZDIVO Z CDm | Půdorys 6.NP | EPS 0.1 m, ZDIVO Z CDm 0.3 m |  | ZDIVO Z CDm | A | 1952HWa0798426613 | m3 | Celá stěna | Stávající | Zateplovací systémy | EPS | no | 1952Stě0798426617 | m2 | Stěna | 0 | 0.4 | 3.58 | 3.49 | 1.402 | 3.53 | 1.366 | 1.402 | 1 | NEMSOK - Object Layer Attributes #2, 2D interakce: yes; Object Layer Attributes #2, Status: Stávající; Object Layer Attributes #2, Práce: Zednické práce; Object Layer Attributes #2, Materiál: ZDIVO Z CDm; Object Layer Attributes #2, Allright_Stavebni_dil_ID: 1952Stě0798426734; Object Layer Attributes #2, Jednotka: m3; Object Layer Attributes #2, Název_objektu: Stěna; Object Layer Attributes #2, Staticky nosná konstrukce: no
ZDIVO Z CDm | Půdorys 6.NP | EPS 0.05 m, ZDIVO Z CDm 0.32 m |  | ZDIVO Z CDm | A | 1952HWa0000002206 | m3 | Celá stěna | Stávající | Zateplovací systémy | EPS | no | 1952Stě0000002207 | m2 | Stěna | 0 | 0.37 | 1 | 1 | 0.354 | 0.975 | 0.354 | 0.354 | 1 | NEMSOK - Object Layer Attributes #2, 2D interakce: yes; Object Layer Attributes #2, Status: Stávající; Object Layer Attributes #2, Práce: Zednické práce; Object Layer Attributes #2, Materiál: ZDIVO Z CDm; Object Layer Attributes #2, Allright_Stavebni_dil_ID: 1952Stě0798426531; Object Layer Attributes #2, Jednotka: m3; Object Layer Attributes #2, Název_objektu: Stěna; Object Layer Attributes #2, Staticky nosná konstrukce: no
ZDIVO Z CDm | Půdorys 6.NP | EPS 0.05 m, ZDIVO Z CDm 0.3 m |  | ZDIVO Z CDm | A | 1952HWa0000002194 | m3 | Celá stěna | Stávající | Zateplovací systémy | EPS | no | 1952Stě0000002195 | m2 | Stěna | 0 | 0.35 | 1.15 | 1.15 | 0.397 | 1.14 | 0.397 | 0.396 | 1 | NEMSOK - Object Layer Attributes #2, 2D interakce: yes; Object Layer Attributes #2, Status: Stávající; Object Layer Attributes #2, Práce: Zednické práce; Object Layer Attributes #2, Materiál: ZDIVO Z CDm; Object Layer Attributes #2, Allright_Stavebni_dil_ID: 1952Stě0798426562; Object Layer Attributes #2, Jednotka: m3; Object Layer Attributes #2, Název_objektu: Stěna; Object Layer Attributes #2, Staticky nosná konstrukce: no
ZELEZOBETONOVÁ KCE | Půdorys 6.NP | EPS 0.05 m, ZELEZOBETONOVÁ KCE 0.32 m |  | ZELEZOBETONOVÁ KCE | A | 1952HWa0000002255 | m3 | Celá stěna | Stávající | Zateplovací systémy | EPS | no | 1952Stě0000002256 | m2 | Stěna | 0 | 0.37 | 12 | 11.82 | 4.32 | 9.6 | 4.253 | 3.552 | 1.25 | NEMSOK - Object Layer Attributes #2, 2D interakce: yes; Object Layer Attributes #2, Status: Stávající; Object Layer Attributes #2, Práce: Betonářské práce; Object Layer Attributes #2, Materiál: ZELEZOBETONOVÁ KCE; Object Layer Attributes #2, Allright_Stavebni_dil_ID: 1952Stě0798426505; Object Layer Attributes #2, Jednotka: m3; Object Layer Attributes #2, Název_objektu: Stěna; Object Layer Attributes #2, Staticky nosná konstrukce: no
ZDIVO Z CDm | Půdorys 6.NP | EPS 0.05 m, ZDIVO Z CDm 0.32 m |  | ZDIVO Z CDm | A | 1952HWa0000002273 | m3 | Celá stěna | Stávající | Zateplovací systémy | EPS | no | 1952Stě0000002274 | m2 | Stěna | 0 | 0.37 | 1 | 1 | 0.354 | 0.975 | 0.354 | 0.354 | 1 | NEMSOK - Object Layer Attributes #2, 2D interakce: yes; Object Layer Attributes #2, Status: Stávající; Object Layer Attributes #2, Práce: Zednické práce; Object Layer Attributes #2, Materiál: ZDIVO Z CDm; Object Layer Attributes #2, Allright_Stavebni_dil_ID: 1952Stě0798426466; Object Layer Attributes #2, Jednotka: m3; Object Layer Attributes #2, Název_objektu: Stěna; Object Layer Attributes #2, Staticky nosná konstrukce: no
ZDIVO Z CDm | Půdorys 6.NP | EPS 0.1 m, ZDIVO Z CDm 0.3 m |  | ZDIVO Z CDm | A | 1952HWa0000002172 | m3 | Celá stěna | Stávající | Zateplovací systémy | EPS | no | 1952Stě0000002173 | m2 | Stěna | 0 | 0.4 | 1.8 | 1.8 | 0.63 | 1.65 | 0.63 | 0.63 | 1 | NEMSOK - Object Layer Attributes #2, 2D interakce: yes; Object Layer Attributes #2, Status: Stávající; Object Layer Attributes #2, Práce: Zednické práce; Object Layer Attributes #2, Materiál: ZDIVO Z CDm; Object Layer Attributes #2, Allright_Stavebni_dil_ID: 1952Stě0798426816; Object Layer Attributes #2, Jednotka: m3; Object Layer Attributes #2, Název_objektu: Stěna; Object Layer Attributes #2, Staticky nosná konstrukce: no
ZDIVO Z CDm | Půdorys 6.NP | EPS 0.1 m, ZDIVO Z CDm 0.3 m |  | ZDIVO Z CDm | A | 1952HWa0798426632 | m3 | Celá stěna | Stávající | Zateplovací systémy | EPS | no | 1952Stě0798426637 | m2 | Stěna | 0 | 0.4 | 3.58 | 3.49 | 1.402 | 3.53 | 1.366 | 1.402 | 1 | NEMSOK - Object Layer Attributes #2, 2D interakce: yes; Object Layer Attributes #2, Status: Stávající; Object Layer Attributes #2, Práce: Zednické práce; Object Layer Attributes #2, Materiál: ZDIVO Z CDm; Object Layer Attributes #2, Allright_Stavebni_dil_ID: 1952Stě0798426636; Object Layer Attributes #2, Jednotka: m3; Object Layer Attributes #2, Název_objektu: Stěna; Object Layer Attributes #2, Staticky nosná konstrukce: no
ZDIVO Z CDm | Půdorys 6.NP | EPS 0.05 m, ZDIVO Z CDm 0.3 m |  | ZDIVO Z CDm | A | 1952HWa0000002183 | m3 | Celá stěna | Stávající | Zateplovací systémy | EPS | no | 1952Stě0000002184 | m2 | Stěna | 0 | 0.35 | 3.67 | 3.58 | 1.282 | 3.645 | 1.25 | 1.282 | 1 | NEMSOK - Object Layer Attributes #2, 2D interakce: yes; Object Layer Attributes #2, Status: Stávající; Object Layer Attributes #2, Práce: Zednické práce; Object Layer Attributes #2, Materiál: ZDIVO Z CDm; Object Layer Attributes #2, Allright_Stavebni_dil_ID: 1952Stě0798426697; Object Layer Attributes #2, Jednotka: m3; Object Layer Attributes #2, Název_objektu: Stěna; Object Layer Attributes #2, Staticky nosná konstrukce: no
 | Půdorys 6.NP | ZELEZOBETONOVÁ KCE 0.3 m | 1 |  |  | 1954HWa0000000356 | m3 | Celá stěna | Stávající | Betonářské práce | ZELEZOBETONOVÁ KCE | yes | 1954Ven0000000357 | m2 | Věnec |  | 0.3 | 1.59 | 1.59 | 0.477 | 0 | 0.477 | 2.385 | 0.2
 | Půdorys 6.NP | ZELEZOBETONOVÁ KCE 0.25 m, LIGNOPOR 0.05 m |  |  |  | 1954HWa0000000183 | m3 | Celá stěna | Stávající | Betonářské práce | ZELEZOBETONOVÁ KCE | yes | 1954Ven0000000184 | m2 | Věnec |  | 0.3 | 1.86 | 1.86 | 0.543 | 0 | 0.543 | 2.715 | 0.2 | NEMSOK - Object Layer Attributes #2, 2D interakce: yes; Object Layer Attributes #2, Status: Stávající; Object Layer Attributes #2, Práce: Zateplovací systémy; Object Layer Attributes #2, Materiál: LIGNOPOR; Object Layer Attributes #2, Allright_Stavebni_dil_ID: 1954Ven0000000185; Object Layer Attributes #2, Jednotka: m2; Object Layer Attributes #2, Název_objektu: Věnec; Object Layer Attributes #2, Staticky nosná konstrukce: no
 | Půdorys 6.NP | ZELEZOBETONOVÁ KCE 0.25 m, LIGNOPOR 0.05 m |  |  |  | 1954HWa0000000191 | m3 | Celá stěna | Stávající | Betonářské práce | ZELEZOBETONOVÁ KCE | yes | 1954Ven0000000192 | m2 | Věnec |  | 0.3 | 1.36 | 1.36 | 0.383 | 0 | 0.383 | 1.915 | 0.2 | NEMSOK - Object Layer Attributes #2, 2D interakce: yes; Object Layer Attributes #2, Status: Stávající; Object Layer Attributes #2, Práce: Zateplovací systémy; Object Layer Attributes #2, Materiál: LIGNOPOR; Object Layer Attributes #2, Allright_Stavebni_dil_ID: 1954Ven0000000193; Object Layer Attributes #2, Jednotka: m2; Object Layer Attributes #2, Název_objektu: Věnec; Object Layer Attributes #2, Staticky nosná konstrukce: no
 | Půdorys 6.NP | ZELEZOBETONOVÁ KCE 0.25 m, LIGNOPOR 0.05 m |  |  |  | 1954HWa0000000224 | m3 | Celá stěna | Stávající | Betonářské práce | ZELEZOBETONOVÁ KCE | yes | 1954Ven0000000225 | m2 | Věnec |  | 0.3 | 0.21 | 0.21 | 0.061 | 0 | 0.061 | 0.305 | 0.2 | NEMSOK - Object Layer Attributes #2, 2D interakce: yes; Object Layer Attributes #2, Status: Stávající; Object Layer Attributes #2, Práce: Zateplovací systémy; Object Layer Attributes #2, Materiál: LIGNOPOR; Object Layer Attributes #2, Allright_Stavebni_dil_ID: 1954Ven0000000226; Object Layer Attributes #2, Jednotka: m2; Object Layer Attributes #2, Název_objektu: Věnec; Object Layer Attributes #2, Staticky nosná konstrukce: no
 | Půdorys 6.NP | ZELEZOBETONOVÁ KCE 0.25 m, LIGNOPOR 0.05 m |  |  |  | 1954HWa0000000232 | m3 | Celá stěna | Stávající | Betonářské práce | ZELEZOBETONOVÁ KCE | yes | 1954Ven0000000233 | m2 | Věnec |  | 0.3 | 0.72 | 0.72 | 0.216 | 0 | 0.216 | 1.08 | 0.2 | NEMSOK - Object Layer Attributes #2, 2D interakce: yes; Object Layer Attributes #2, Status: Stávající; Object Layer Attributes #2, Práce: Zateplovací systémy; Object Layer Attributes #2, Materiál: LIGNOPOR; Object Layer Attributes #2, Allright_Stavebni_dil_ID: 1954Ven0000000234; Object Layer Attributes #2, Jednotka: m2; Object Layer Attributes #2, Název_objektu: Věnec; Object Layer Attributes #2, Staticky nosná konstrukce: no
 | Půdorys 6.NP | ZELEZOBETONOVÁ KCE 0.25 m, LIGNOPOR 0.05 m |  |  |  | 1954HWa0000000253 | m3 | Celá stěna | Stávající | Betonářské práce | ZELEZOBETONOVÁ KCE | yes | 1954Ven0000000254 | m2 | Věnec |  | 0.3 | 1.7 | 1.7 | 0.495 | 0 | 0.495 | 2.475 | 0.2 | NEMSOK - Object Layer Attributes #2, 2D interakce: yes; Object Layer Attributes #2, Status: Stávající; Object Layer Attributes #2, Práce: Zateplovací systémy; Object Layer Attributes #2, Materiál: LIGNOPOR; Object Layer Attributes #2, Allright_Stavebni_dil_ID: 1954Ven0000000255; Object Layer Attributes #2, Jednotka: m2; Object Layer Attributes #2, Název_objektu: Věnec; Object Layer Attributes #2, Staticky nosná konstrukce: no
 | Půdorys 6.NP | ZELEZOBETONOVÁ KCE 0.25 m, LIGNOPOR 0.05 m |  |  |  | 1954HWa0000000274 | m3 | Celá stěna | Stávající | Betonářské práce | ZELEZOBETONOVÁ KCE | yes | 1954Ven0000000275 | m2 | Věnec |  | 0.3 | 2.09 | 2.09 | 0.612 | 0 | 0.612 | 3.06 | 0.2 | NEMSOK - Object Layer Attributes #2, 2D interakce: yes; Object Layer Attributes #2, Status: Stávající; Object Layer Attributes #2, Práce: Zateplovací systémy; Object Layer Attributes #2, Materiál: LIGNOPOR; Object Layer Attributes #2, Allright_Stavebni_dil_ID: 1954Ven0000000276; Object Layer Attributes #2, Jednotka: m2; Object Layer Attributes #2, Název_objektu: Věnec; Object Layer Attributes #2, Staticky nosná konstrukce: no
MINERÁLNÍ VATA | Půdorys 6.NP | YTONG 150 0.15 m, MINERÁLNÍ VATA 0.15 m |  | MINERÁLNÍ VATA |  | 1964HWa0000003516 | m3 | Celá stěna | Nový | Zednické práce | YTONG 150 | no | 1964Stě0000003518 | m2 | Stěna |  | 0.3 | 0.426 | 0.426 | 0.097 | 0.295 | 0.097 | 0.089 | 1.15 | NEMSOK - Object Layer Attributes #2, 2D interakce: yes; Object Layer Attributes #2, Status: Nový; Object Layer Attributes #2, Práce: Zateplovací systémy; Object Layer Attributes #2, Materiál: MINERÁLNÍ VATA; Object Layer Attributes #2, Allright_Stavebni_dil_ID: 1964Stě0000003519; Object Layer Attributes #2, Jednotka: m3; Object Layer Attributes #2, Název_objektu: Stěna; Object Layer Attributes #2, Staticky nosná konstrukce: no; Object Layer Attributes #1, Kód prvku: SN06.07.0001; Object Layer Attributes #1, U-hodnota: 1.111; Object Layer Attributes #1, Podlaží: 6.NP; Object Layer Attributes #1, Neprůzvučnost: 35 dB; Object Layer Attributes #1, Pevnost zdiva: 1,92 N/mm2; Object Layer Attributes #1, Funkce (venkovní): Ano; Object Layer Attributes #2, Kód prvku: TI06.07.1016; Object Layer Attributes #2, Požární odolnost: A1; Object Layer Attributes #2, Součinitel prostupu tepla: 0.036; Object Layer Attributes #2, Součinitel difúzního odporu: 1; Object Layer Attributes #2, Způsob spojení vrstev: Lepený + mechanicky kotvený; Object Layer Attributes #2, Systém kotvení: -
MINERÁLNÍ VATA | Půdorys 6.NP | YTONG 150 0.15 m, MINERÁLNÍ VATA 0.15 m |  | MINERÁLNÍ VATA |  | 1964HWa0000003512 | m3 | Celá stěna | Nový | Zednické práce | YTONG 150 | no | 1964Stě0000003523 | m2 | Stěna |  | 0.3 | 0.748 | 0.748 | 0.165 | 0.5 | 0.165 | 0.15 | 1.15 | NEMSOK - Object Layer Attributes #2, 2D interakce: yes; Object Layer Attributes #2, Status: Nový; Object Layer Attributes #2, Práce: Zateplovací systémy; Object Layer Attributes #2, Materiál: MINERÁLNÍ VATA; Object Layer Attributes #2, Allright_Stavebni_dil_ID: 1964Stě0000003522; Object Layer Attributes #2, Jednotka: m3; Object Layer Attributes #2, Název_objektu: Stěna; Object Layer Attributes #2, Staticky nosná konstrukce: no; Object Layer Attributes #1, Kód prvku: SN06.07.0001; Object Layer Attributes #1, U-hodnota: 1.111; Object Layer Attributes #1, Podlaží: 6.NP; Object Layer Attributes #1, Neprůzvučnost: 35 dB; Object Layer Attributes #1, Pevnost zdiva: 1,92 N/mm2; Object Layer Attributes #1, Funkce (venkovní): Ano; Object Layer Attributes #2, Kód prvku: TI06.07.1017; Object Layer Attributes #2, Požární odolnost: A1; Object Layer Attributes #2, Součinitel prostupu tepla: 0.036; Object Layer Attributes #2, Součinitel difúzního odporu: 1; Object Layer Attributes #2, Způsob spojení vrstev: Lepený + mechanicky kotvený; Object Layer Attributes #2, Systém kotvení: -
MINERÁLNÍ VATA | Půdorys 6.NP | YTONG 150 0.15 m, MINERÁLNÍ VATA 0.15 m |  | MINERÁLNÍ VATA |  | 1964HWa0000003510 | m3 | Celá stěna | Nový | Zednické práce | YTONG 150 | no | 1964Stě0000003515 | m2 | Stěna |  | 0.3 | 0.253 | 0.253 | 0.048 | 0.145 | 0.048 | 0.044 | 1.15 | NEMSOK - Object Layer Attributes #2, 2D interakce: yes; Object Layer Attributes #2, Status: Nový; Object Layer Attributes #2, Práce: Zateplovací systémy; Object Layer Attributes #2, Materiál: MINERÁLNÍ VATA; Object Layer Attributes #2, Allright_Stavebni_dil_ID: 1964Stě0000003514; Object Layer Attributes #2, Jednotka: m3; Object Layer Attributes #2, Název_objektu: Stěna; Object Layer Attributes #2, Staticky nosná konstrukce: no; Object Layer Attributes #1, Kód prvku: SN06.07.0001; Object Layer Attributes #1, U-hodnota: 1.111; Object Layer Attributes #1, Podlaží: 6.NP; Object Layer Attributes #1, Neprůzvučnost: 35 dB; Object Layer Attributes #1, Pevnost zdiva: 1,92 N/mm2; Object Layer Attributes #1, Funkce (venkovní): Ano; Object Layer Attributes #2, Kód prvku: TI06.07.1015; Object Layer Attributes #2, Požární odolnost: A1; Object Layer Attributes #2, Součinitel prostupu tepla: 0.036; Object Layer Attributes #2, Součinitel difúzního odporu: 1; Object Layer Attributes #2, Způsob spojení vrstev: Lepený + mechanicky kotvený; Object Layer Attributes #2, Systém kotvení: -
MINERÁLNÍ VATA | Půdorys 6.NP | YTONG 150 0.15 m, MINERÁLNÍ VATA 0.15 m |  | MINERÁLNÍ VATA |  | 1964HWa0000003494 | m3 | Celá stěna | Nový | Zednické práce | YTONG 150 | no | 1964Stě0000003500 | m2 | Stěna |  | 0.3 | 0.748 | 0.629 | 0.165 | 0.5 | 0.147 | 0.15 | 1.15 | NEMSOK - Object Layer Attributes #2, 2D interakce: yes; Object Layer Attributes #2, Status: Nový; Object Layer Attributes #2, Práce: Zateplovací systémy; Object Layer Attributes #2, Materiál: MINERÁLNÍ VATA; Object Layer Attributes #2, Allright_Stavebni_dil_ID: 1964Stě0000003499; Object Layer Attributes #2, Jednotka: m3; Object Layer Attributes #2, Název_objektu: Stěna; Object Layer Attributes #2, Staticky nosná konstrukce: no; Object Layer Attributes #1, Kód prvku: SN06.07.0001; Object Layer Attributes #1, U-hodnota: 1.111; Object Layer Attributes #1, Podlaží: 6.NP; Object Layer Attributes #1, Neprůzvučnost: 35 dB; Object Layer Attributes #1, Pevnost zdiva: 1,92 N/mm2; Object Layer Attributes #1, Funkce (venkovní): Ano; Object Layer Attributes #2, Kód prvku: TI06.07.1011; Object Layer Attributes #2, Požární odolnost: A1; Object Layer Attributes #2, Součinitel prostupu tepla: 0.036; Object Layer Attributes #2, Součinitel difúzního odporu: 1; Object Layer Attributes #2, Způsob spojení vrstev: Lepený + mechanicky kotvený; Object Layer Attributes #2, Systém kotvení: -
MINERÁLNÍ VATA | Půdorys 6.NP | YTONG 150 0.15 m, MINERÁLNÍ VATA 0.15 m |  | MINERÁLNÍ VATA |  | 1964HWa0000003497 | m3 | Celá stěna | Nový | Zednické práce | YTONG 150 | no | 1964Stě0000003508 | m2 | Stěna |  | 0.3 | 0.748 | 0.748 | 0.165 | 0.5 | 0.165 | 0.15 | 1.15 | NEMSOK - Object Layer Attributes #2, 2D interakce: yes; Object Layer Attributes #2, Status: Nový; Object Layer Attributes #2, Práce: Zateplovací systémy; Object Layer Attributes #2, Materiál: MINERÁLNÍ VATA; Object Layer Attributes #2, Allright_Stavebni_dil_ID: 1964Stě0000003507; Object Layer Attributes #2, Jednotka: m3; Object Layer Attributes #2, Název_objektu: Stěna; Object Layer Attributes #2, Staticky nosná konstrukce: no; Object Layer Attributes #1, Kód prvku: SN06.07.0001; Object Layer Attributes #1, U-hodnota: 1.111; Object Layer Attributes #1, Podlaží: 6.NP; Object Layer Attributes #1, Neprůzvučnost: 35 dB; Object Layer Attributes #1, Pevnost zdiva: 1,92 N/mm2; Object Layer Attributes #1, Funkce (venkovní): Ano; Object Layer Attributes #2, Kód prvku: TI06.07.1013; Object Layer Attributes #2, Požární odolnost: A1; Object Layer Attributes #2, Součinitel prostupu tepla: 0.036; Object Layer Attributes #2, Součinitel difúzního odporu: 1; Object Layer Attributes #2, Způsob spojení vrstev: Lepený + mechanicky kotvený; Object Layer Attributes #2, Systém kotvení: -
MINERÁLNÍ VATA | Půdorys 6.NP | YTONG 150 0.15 m, MINERÁLNÍ VATA 0.15 m |  | MINERÁLNÍ VATA |  | 1964HWa0000003501 | m3 | Celá stěna | Nový | Zednické práce | YTONG 150 | no | 1964Stě0000003504 | m2 | Stěna |  | 0.3 | 0.402 | 0.403 | 0.09 | 0.275 | 0.09 | 0.083 | 1.15 | NEMSOK - Object Layer Attributes #2, 2D interakce: yes; Object Layer Attributes #2, Status: Nový; Object Layer Attributes #2, Práce: Zateplovací systémy; Object Layer Attributes #2, Materiál: MINERÁLNÍ VATA; Object Layer Attributes #2, Allright_Stavebni_dil_ID: 1964Stě0000003505; Object Layer Attributes #2, Jednotka: m3; Object Layer Attributes #2, Název_objektu: Stěna; Object Layer Attributes #2, Staticky nosná konstrukce: no; Object Layer Attributes #1, Kód prvku: SN06.07.0001; Object Layer Attributes #1, U-hodnota: 1.111; Object Layer Attributes #1, Podlaží: 6.NP; Object Layer Attributes #1, Neprůzvučnost: 35 dB; Object Layer Attributes #1, Pevnost zdiva: 1,92 N/mm2; Object Layer Attributes #1, Funkce (venkovní): Ano; Object Layer Attributes #2, Kód prvku: TI06.07.1012; Object Layer Attributes #2, Požární odolnost: A1; Object Layer Attributes #2, Součinitel prostupu tepla: 0.036; Object Layer Attributes #2, Součinitel difúzního odporu: 1; Object Layer Attributes #2, Způsob spojení vrstev: Lepený + mechanicky kotvený; Object Layer Attributes #2, Systém kotvení: -
MINERÁLNÍ VATA | Půdorys 6.NP | MINERÁLNÍ VATA 0.15 m |  | MINERÁLNÍ VATA |  | 1964HWa0000003328 | m3 | Celá stěna | Nový | Zateplovací systémy | MINERÁLNÍ VATA | no | 1964Stě0000003422 | m3 | Stěna |  | 0.15 | 0.949 | 0.949 | 0.142 | 1.13 | 0.142 | 0.169 | 0.84 | NEMSOK - Object Layer Attributes #1, Kód prvku: TI06.07.1008; Object Layer Attributes #1, Požární odolnost: A1; Systém kotvení: -; Object Layer Attributes #1, Systém kotvení: -; Object Layer Attributes #1, Součinitel prostupu tepla: 0.036; Object Layer Attributes #1, Součinitel difúzního odporu: 1; Object Layer Attributes #1, Způsob spojení vrstev: Lepený + mechanicky kotvený
MINERÁLNÍ VATA | Půdorys 6.NP | MINERÁLNÍ VATA 0.15 m |  | MINERÁLNÍ VATA |  | 1964HWa0000003330 | m3 | Celá stěna | Nový | Zateplovací systémy | MINERÁLNÍ VATA | no | 1964Stě0000003421 | m3 | Stěna |  | 0.15 | 8.887 | 8.887 | 1.333 | 10.58 | 1.333 | 1.587 | 0.84 | NEMSOK - Object Layer Attributes #1, Kód prvku: TI06.07.1007; Object Layer Attributes #1, Požární odolnost: A1; Systém kotvení: -; Object Layer Attributes #1, Systém kotvení: -; Object Layer Attributes #1, Součinitel prostupu tepla: 0.036; Object Layer Attributes #1, Součinitel difúzního odporu: 1; Object Layer Attributes #1, Způsob spojení vrstev: Lepený + mechanicky kotvený
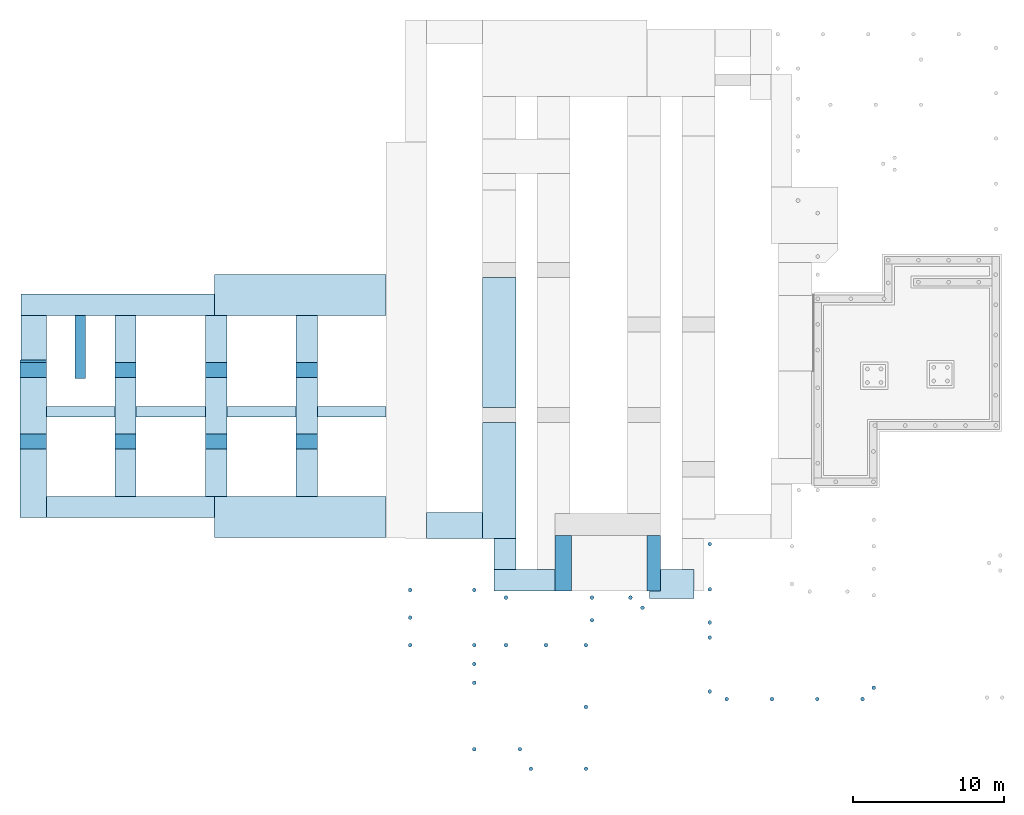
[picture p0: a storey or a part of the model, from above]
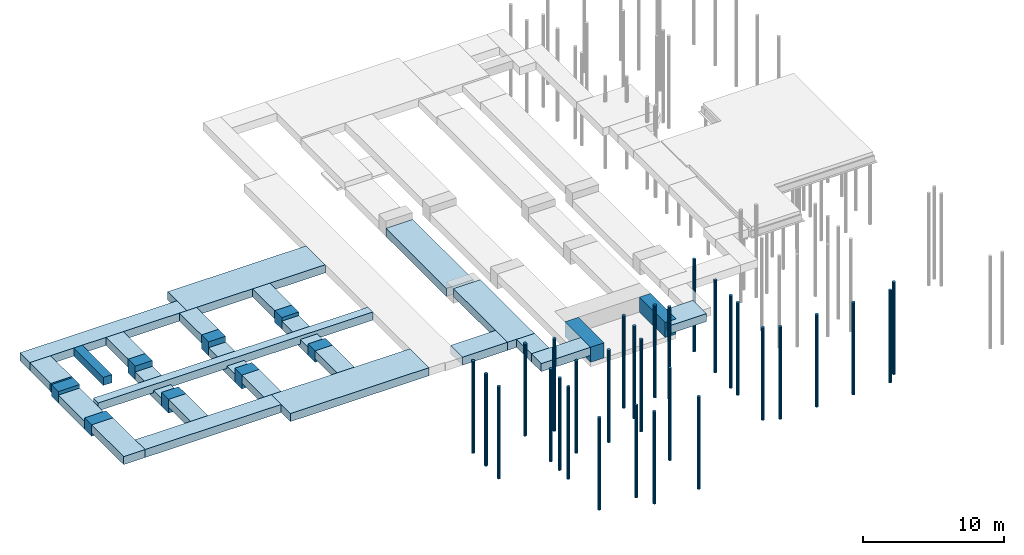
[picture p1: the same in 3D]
Properties of the parts of a building model (IFC4), part 43 of 45

# IfcWall (2385)
Name | In | Material | Faktor | Označení | Požární odolnost | Allright_Stavebni_dil_ID | Jednotka | Název_objektu | Object Layer Attributes #1, Status | Object Layer Attributes #1, Práce | Object Layer Attributes #1, Materiál | Object Layer Attributes #1, Staticky nosná konstrukce | Object Layer Attributes #1, Allright_Stavebni_dil_ID | Object Layer Attributes #1, Jednotka | Object Layer Attributes #1, Název_objektu | ThermalTransmittance (W/K/m2) | Width (m) | GrossSideArea (m2) | NetSideArea (m2) | GrossVolume (m3) | Length (m) | NetVolume (m3) | GrossFootprintArea (m2) | Height (m)
MINERÁLNÍ VATA | Půdorys 6.NP | MINERÁLNÍ VATA 0.15 m |  | MINERÁLNÍ VATA |  | 1964HWa0000003333 | m3 | Celá stěna | Nový | Zateplovací systémy | MINERÁLNÍ VATA | no | 1964Stě0000003420 | m3 | Stěna |  | 0.15 | 6.006 | 6.006 | 0.901 | 7.15 | 0.901 | 1.072 | 0.84 | NEMSOK - Object Layer Attributes #1, Kód prvku: TI06.07.1006; Object Layer Attributes #1, Požární odolnost: A1; Systém kotvení: -; Object Layer Attributes #1, Systém kotvení: -; Object Layer Attributes #1, Součinitel prostupu tepla: 0.036; Object Layer Attributes #1, Součinitel difúzního odporu: 1; Object Layer Attributes #1, Způsob spojení vrstev: Lepený + mechanicky kotvený
MINERÁLNÍ VATA | Půdorys 6.NP | MINERÁLNÍ VATA 0.15 m |  | MINERÁLNÍ VATA |  | 1964HWa0000003337 | m3 | Celá stěna | Nový | Zateplovací systémy | MINERÁLNÍ VATA | no | 1964Stě0000003524 | m3 | Stěna |  | 0.15 | 6.01 | 6.006 | 0.902 | 7.155 | 0.902 | 1.073 | 0.84 | NEMSOK - Object Layer Attributes #1, Kód prvku: TI06.07.1018; Object Layer Attributes #1, Požární odolnost: A1; Systém kotvení: -; Object Layer Attributes #1, Systém kotvení: -; Object Layer Attributes #1, Součinitel prostupu tepla: 0.036; Object Layer Attributes #1, Součinitel difúzního odporu: 1; Object Layer Attributes #1, Způsob spojení vrstev: Lepený + mechanicky kotvený
MINERÁLNÍ VATA | Půdorys 6.NP | MINERÁLNÍ VATA 0.15 m |  | MINERÁLNÍ VATA |  | 1964HWa0000003338 | m3 | Celá stěna | Nový | Zateplovací systémy | MINERÁLNÍ VATA | no | 1964Stě0000003427 | m3 | Stěna |  | 0.15 | 11.126 | 11.126 | 1.669 | 13.245 | 1.669 | 1.987 | 0.84 | NEMSOK - Object Layer Attributes #1, Kód prvku: TI06.07.1010; Object Layer Attributes #1, Požární odolnost: A1; Systém kotvení: -; Object Layer Attributes #1, Systém kotvení: -; Object Layer Attributes #1, Součinitel prostupu tepla: 0.036; Object Layer Attributes #1, Součinitel difúzního odporu: 1; Object Layer Attributes #1, Způsob spojení vrstev: Lepený + mechanicky kotvený
MINERÁLNÍ VATA | Půdorys 6.NP | MINERÁLNÍ VATA 0.15 m |  | MINERÁLNÍ VATA |  | 1964HWa0000003341 | m3 | Celá stěna | Nový | Zateplovací systémy | MINERÁLNÍ VATA | no | 1964Stě0000003415 | m3 | Stěna |  | 0.15 | 13.154 | 13.154 | 1.973 | 15.66 | 1.973 | 2.349 | 0.84 | NEMSOK - Object Layer Attributes #1, Kód prvku: TI06.07.1001; Object Layer Attributes #1, Požární odolnost: A1; Systém kotvení: -; Object Layer Attributes #1, Systém kotvení: -; Object Layer Attributes #1, Součinitel prostupu tepla: 0.036; Object Layer Attributes #1, Součinitel difúzního odporu: 1; Object Layer Attributes #1, Způsob spojení vrstev: Lepený + mechanicky kotvený
MINERÁLNÍ VATA | Půdorys 6.NP | MINERÁLNÍ VATA 0.15 m |  | MINERÁLNÍ VATA |  | 1964HWa0000003343 | m3 | Celá stěna | Nový | Zateplovací systémy | MINERÁLNÍ VATA | no | 1964Stě0000003426 | m3 | Stěna |  | 0.15 | 0.949 | 0.949 | 0.142 | 1.13 | 0.142 | 0.169 | 0.84 | NEMSOK - Object Layer Attributes #1, Kód prvku: TI06.07.1009; Object Layer Attributes #1, Požární odolnost: A1; Systém kotvení: -; Object Layer Attributes #1, Systém kotvení: -; Object Layer Attributes #1, Součinitel prostupu tepla: 0.036; Object Layer Attributes #1, Součinitel difúzního odporu: 1; Object Layer Attributes #1, Způsob spojení vrstev: Lepený + mechanicky kotvený
MINERÁLNÍ VATA | Půdorys 6.NP | MINERÁLNÍ VATA 0.15 m |  | MINERÁLNÍ VATA |  | 1964HWa0000003346 | m3 | Celá stěna | Nový | Zateplovací systémy | MINERÁLNÍ VATA | no | 1964Stě0000003418 | m3 | Stěna |  | 0.15 | 1.95 | 1.95 | 0.293 | 1.5 | 0.293 | 0.225 | 1.3 | NEMSOK - Object Layer Attributes #1, Kód prvku: TI06.07.1004; Object Layer Attributes #1, Požární odolnost: A1; Systém kotvení: -; Object Layer Attributes #1, Systém kotvení: -; Object Layer Attributes #1, Součinitel prostupu tepla: 0.036; Object Layer Attributes #1, Součinitel difúzního odporu: 1; Object Layer Attributes #1, Způsob spojení vrstev: Lepený + mechanicky kotvený
MINERÁLNÍ VATA | Půdorys 6.NP | MINERÁLNÍ VATA 0.15 m |  | MINERÁLNÍ VATA |  | 1964HWa0000003348 | m3 | Celá stěna | Nový | Zateplovací systémy | MINERÁLNÍ VATA | no | 1964Stě0000003416 | m3 | Stěna |  | 0.15 | 1.95 | 1.95 | 0.293 | 1.5 | 0.293 | 0.225 | 1.3 | NEMSOK - Object Layer Attributes #1, Kód prvku: TI06.07.1002; Object Layer Attributes #1, Požární odolnost: A1; Systém kotvení: -; Object Layer Attributes #1, Systém kotvení: -; Object Layer Attributes #1, Součinitel prostupu tepla: 0.036; Object Layer Attributes #1, Součinitel difúzního odporu: 1; Object Layer Attributes #1, Způsob spojení vrstev: Lepený + mechanicky kotvený
MINERÁLNÍ VATA | Půdorys 6.NP | MINERÁLNÍ VATA 0.15 m |  | MINERÁLNÍ VATA |  | 1964HWa0000003350 | m3 | Celá stěna | Nový | Zateplovací systémy | MINERÁLNÍ VATA | no | 1964Stě0000003419 | m3 | Stěna |  | 0.15 | 0.78 | 0.78 | 0.117 | 0.6 | 0.117 | 0.09 | 1.3 | NEMSOK - Object Layer Attributes #1, Kód prvku: TI06.07.1005; Object Layer Attributes #1, Požární odolnost: A1; Systém kotvení: -; Object Layer Attributes #1, Systém kotvení: -; Object Layer Attributes #1, Součinitel prostupu tepla: 0.036; Object Layer Attributes #1, Součinitel difúzního odporu: 1; Object Layer Attributes #1, Způsob spojení vrstev: Lepený + mechanicky kotvený
MINERÁLNÍ VATA | Půdorys 6.NP | MINERÁLNÍ VATA 0.15 m |  | MINERÁLNÍ VATA |  | 1964HWa0000003352 | m3 | Celá stěna | Nový | Zateplovací systémy | MINERÁLNÍ VATA | no | 1964Stě0000003417 | m3 | Stěna |  | 0.15 | 0.78 | 0.78 | 0.117 | 0.6 | 0.117 | 0.09 | 1.3 | NEMSOK - Object Layer Attributes #1, Kód prvku: TI06.07.1003; Object Layer Attributes #1, Požární odolnost: A1; Systém kotvení: -; Object Layer Attributes #1, Systém kotvení: -; Object Layer Attributes #1, Součinitel prostupu tepla: 0.036; Object Layer Attributes #1, Součinitel difúzního odporu: 1; Object Layer Attributes #1, Způsob spojení vrstev: Lepený + mechanicky kotvený
MINERÁLNÍ VATA | Půdorys 6.NP | MINERÁLNÍ VATA 0.15 m |  | MINERÁLNÍ VATA |  | 1964HWa0000003413 | m3 | Celá stěna | Nový | Zateplovací systémy | MINERÁLNÍ VATA | no | 1964Stě0000003509 | m3 | Stěna |  | 0.15 | 9.013 | 9.013 | 1.352 | 10.73 | 1.352 | 1.61 | 0.84 | NEMSOK - Object Layer Attributes #1, Kód prvku: TI06.07.1014; Object Layer Attributes #1, Požární odolnost: A1; Systém kotvení: -; Object Layer Attributes #1, Systém kotvení: -; Object Layer Attributes #1, Součinitel prostupu tepla: 0.036; Object Layer Attributes #1, Součinitel difúzního odporu: 1; Object Layer Attributes #1, Způsob spojení vrstev: Lepený + mechanicky kotvený
ZDIVO Z CDm | Půdorys střechy | EPS 0.1 m, ZDIVO Z CDm 0.25 m |  | ZDIVO Z CDm | A | 2477HWa0000000049 | m3 | Celá stěna | Stávající | Zateplovací systémy | EPS | no | 2477Stě0000000050 | m2 | Stěna | 0 | 0.35 | 19.635 | 19.636 | 6.816 | 8.6 | 6.816 | 3.002 | 2.27 | NEMSOK - Object Layer Attributes #2, 2D interakce: yes; Object Layer Attributes #2, Status: Stávající; Object Layer Attributes #2, Práce: Zednické práce; Object Layer Attributes #2, Materiál: ZDIVO Z CDm; Object Layer Attributes #2, Allright_Stavebni_dil_ID: 2477Stě0000000742; Object Layer Attributes #2, Jednotka: m3; Object Layer Attributes #2, Název_objektu: Stěna; Object Layer Attributes #2, Staticky nosná konstrukce: yes
ZDIVO Z CDm | Půdorys střechy | EPS 0.1 m, ZDIVO Z CDm 0.25 m |  | ZDIVO Z CDm | A | 2477HWa0000000060 | m3 | Celá stěna | Stávající | Zateplovací systémy | EPS | no | 2477Stě0000000061 | m2 | Stěna | 0 | 0.35 | 24.062 | 24.062 | 8.223 | 10.425 | 8.223 | 3.622 | 2.27 | NEMSOK - Object Layer Attributes #2, 2D interakce: yes; Object Layer Attributes #2, Status: Stávající; Object Layer Attributes #2, Práce: Zednické práce; Object Layer Attributes #2, Materiál: ZDIVO Z CDm; Object Layer Attributes #2, Allright_Stavebni_dil_ID: 2477Stě0000000762; Object Layer Attributes #2, Jednotka: m3; Object Layer Attributes #2, Název_objektu: Stěna; Object Layer Attributes #2, Staticky nosná konstrukce: yes
ZDIVO Z CDm | Půdorys střechy | EPS 0.1 m, ZDIVO Z CDm 0.25 m |  | ZDIVO Z CDm | A | 2477HWa0000000169 | m3 | Celá stěna | Stávající | Zateplovací systémy | EPS | no | 2477Stě0000000171 | m2 | Stěna | 0 | 0.35 | 21.224 | 21.045 | 7.145 | 9.1 | 7.082 | 3.147 | 2.27 | NEMSOK - Object Layer Attributes #2, 2D interakce: yes; Object Layer Attributes #2, Status: Stávající; Object Layer Attributes #2, Práce: Zednické práce; Object Layer Attributes #2, Materiál: ZDIVO Z CDm; Object Layer Attributes #2, Allright_Stavebni_dil_ID: 2477Stě0000000781; Object Layer Attributes #2, Jednotka: m3; Object Layer Attributes #2, Název_objektu: Stěna; Object Layer Attributes #2, Staticky nosná konstrukce: yes
ZDIVO Z CDm | Půdorys střechy | EPS 0.1 m, ZDIVO Z CDm 0.25 m |  | ZDIVO Z CDm | A | 2477HWa0000000021 | m3 | Celá stěna | Stávající | Zateplovací systémy | EPS | no | 2477Stě0000000022 | m2 | Stěna | 0 | 0.35 | 16.117 | 15.869 | 5.386 | 6.875 | 5.299 | 2.372 | 2.27 | NEMSOK - Object Layer Attributes #2, 2D interakce: yes; Object Layer Attributes #2, Status: Stávající; Object Layer Attributes #2, Práce: Zednické práce; Object Layer Attributes #2, Materiál: ZDIVO Z CDm; Object Layer Attributes #2, Allright_Stavebni_dil_ID: 2477Stě0000000627; Object Layer Attributes #2, Jednotka: m3; Object Layer Attributes #2, Název_objektu: Stěna; Object Layer Attributes #2, Staticky nosná konstrukce: yes
ZDIVO Z CDm | Půdorys střechy | EPS 0.1 m, ZDIVO Z CDm 0.25 m |  | ZDIVO Z CDm | A | 2477HWa0000000026 | m3 | Celá stěna | Stávající | Zateplovací systémy | EPS | no | 2477Stě0000000027 | m2 | Stěna | 0 | 0.35 | 2.384 | 2.384 | 0.777 | 0.925 | 0.777 | 0.343 | 2.27 | NEMSOK - Object Layer Attributes #2, 2D interakce: yes; Object Layer Attributes #2, Status: Stávající; Object Layer Attributes #2, Práce: Zednické práce; Object Layer Attributes #2, Materiál: ZDIVO Z CDm; Object Layer Attributes #2, Allright_Stavebni_dil_ID: 2477Stě0000000675; Object Layer Attributes #2, Jednotka: m3; Object Layer Attributes #2, Název_objektu: Stěna; Object Layer Attributes #2, Staticky nosná konstrukce: yes
ZDIVO Z CDm | Půdorys střechy | EPS 0.1 m, ZDIVO Z CDm 0.25 m |  | ZDIVO Z CDm | A | 2477HWa0000000037 | m3 | Celá stěna | Stávající | Zateplovací systémy | EPS | no | 2477Stě0000000038 | m2 | Stěna | 0 | 0.35 | 8.172 | 8.082 | 2.718 | 3.475 | 2.687 | 1.197 | 2.27 | NEMSOK - Object Layer Attributes #2, 2D interakce: yes; Object Layer Attributes #2, Status: Stávající; Object Layer Attributes #2, Práce: Zednické práce; Object Layer Attributes #2, Materiál: ZDIVO Z CDm; Object Layer Attributes #2, Allright_Stavebni_dil_ID: 2477Stě0000000695; Object Layer Attributes #2, Jednotka: m3; Object Layer Attributes #2, Název_objektu: Stěna; Object Layer Attributes #2, Staticky nosná konstrukce: yes
ZDIVO Z CDm | Půdorys střechy | ZDIVO Z CDm 0.15 m |  | ZDIVO Z CDm | A | 2477HWa0000001296 | m3 | Celá stěna | Stávající | Zednické práce | ZDIVO Z CDm | no | 2477Stě0000001297 | m3 | Stěna | 0 | 0.15 | 0.855 | 0.855 | 0.128 | 0.9 | 0.128 | 0.135 | 0.95
ZDIVO Z CDm | Půdorys střechy | ZDIVO Z CDm 0.15 m |  | ZDIVO Z CDm | A | 2477HWa0000001286 | m3 | Celá stěna | Stávající | Zednické práce | ZDIVO Z CDm | no | 2477Stě0000001287 | m3 | Stěna | 0 | 0.15 | 0.713 | 0.713 | 0.107 | 0.75 | 0.107 | 0.113 | 0.95
ZDIVO Z CDm | Půdorys střechy | ZDIVO Z CDm 0.15 m |  | ZDIVO Z CDm | A | 2477HWa0000001281 | m3 | Celá stěna | Stávající | Zednické práce | ZDIVO Z CDm | no | 2477Stě0000001282 | m3 | Stěna | 0 | 0.15 | 1.14 | 1.14 | 0.171 | 1.2 | 0.171 | 0.18 | 0.95
ZDIVO Z CDm | Půdorys střechy | ZDIVO Z CDm 0.15 m |  | ZDIVO Z CDm | A | 2477HWa0000001308 | m3 | Celá stěna | Stávající | Zednické práce | ZDIVO Z CDm | no | 2477Stě0000001309 | m3 | Stěna | 0 | 0.15 | 0.713 | 0.713 | 0.107 | 0.75 | 0.107 | 0.113 | 0.95
MINERÁLNÍ VATA | Půdorys střechy | MINERÁLNÍ VATA 0.15 m |  | MINERÁLNÍ VATA |  | 2481HWa0000000118 | m3 | Celá stěna | Nový | Zateplovací systémy | MINERÁLNÍ VATA | no | 2481Stě0000000138 | m3 | Stěna |  | 0.15 | 1.909 | 1.91 | 0.286 | 0.95 | 0.286 | 0.142 | 2.01 | NEMSOK - Object Layer Attributes #1, Kód prvku: TI06.08.1001; Object Layer Attributes #1, Požární odolnost: A1; Systém kotvení: -; Object Layer Attributes #1, Systém kotvení: -; Object Layer Attributes #1, Součinitel prostupu tepla: 0.036; Object Layer Attributes #1, Součinitel difúzního odporu: 1; Object Layer Attributes #1, Způsob spojení vrstev: Lepený + mechanicky kotvený
MINERÁLNÍ VATA | Půdorys střechy | MINERÁLNÍ VATA 0.15 m |  | MINERÁLNÍ VATA |  | 2481HWa0000000120 | m3 | Celá stěna | Nový | Zateplovací systémy | MINERÁLNÍ VATA | no | 2481Stě0000000144 | m3 | Stěna |  | 0.15 | 12.562 | 12.563 | 1.884 | 6.25 | 1.884 | 0.937 | 2.01 | NEMSOK - Object Layer Attributes #1, Kód prvku: TI06.08.1001; Object Layer Attributes #1, Požární odolnost: A1; Systém kotvení: -; Object Layer Attributes #1, Systém kotvení: -; Object Layer Attributes #1, Součinitel prostupu tepla: 0.036; Object Layer Attributes #1, Součinitel difúzního odporu: 1; Object Layer Attributes #1, Způsob spojení vrstev: Lepený + mechanicky kotvený
MINERÁLNÍ VATA | Půdorys střechy | MINERÁLNÍ VATA 0.15 m |  | MINERÁLNÍ VATA |  | 2481HWa0000000122 | m3 | Celá stěna | Nový | Zateplovací systémy | MINERÁLNÍ VATA | no | 2481Stě0000000127 | m3 | Stěna |  | 0.15 | 17.487 | 17.487 | 2.623 | 8.7 | 2.623 | 1.305 | 2.01 | NEMSOK - Object Layer Attributes #1, Kód prvku: TI06.08.1001; Object Layer Attributes #1, Požární odolnost: A1; Systém kotvení: -; Object Layer Attributes #1, Systém kotvení: -; Object Layer Attributes #1, Součinitel prostupu tepla: 0.036; Object Layer Attributes #1, Součinitel difúzního odporu: 1; Object Layer Attributes #1, Způsob spojení vrstev: Lepený + mechanicky kotvený
MINERÁLNÍ VATA | Půdorys střechy | MINERÁLNÍ VATA 0.15 m |  | MINERÁLNÍ VATA |  | 2481HWa0000000125 | m3 | Celá stěna | Nový | Zateplovací systémy | MINERÁLNÍ VATA | no | 2481Stě0000000132 | m3 | Stěna |  | 0.15 | 19.798 | 19.799 | 2.97 | 9.85 | 2.97 | 1.477 | 2.01 | NEMSOK - Object Layer Attributes #1, Kód prvku: TI06.08.1001; Object Layer Attributes #1, Požární odolnost: A1; Systém kotvení: -; Object Layer Attributes #1, Systém kotvení: -; Object Layer Attributes #1, Součinitel prostupu tepla: 0.036; Object Layer Attributes #1, Součinitel difúzního odporu: 1; Object Layer Attributes #1, Způsob spojení vrstev: Lepený + mechanicky kotvený
MINERÁLNÍ VATA | Půdorys střechy | MINERÁLNÍ VATA 0.15 m |  | MINERÁLNÍ VATA |  | 2481HWa0000000130 | m3 | Celá stěna | Nový | Zateplovací systémy | MINERÁLNÍ VATA | no | 2481Stě0000000142 | m3 | Stěna |  | 0.15 | 15.879 | 15.879 | 2.382 | 7.9 | 2.382 | 1.185 | 2.01 | NEMSOK - Object Layer Attributes #1, Kód prvku: TI06.08.1001; Object Layer Attributes #1, Požární odolnost: A1; Systém kotvení: -; Object Layer Attributes #1, Systém kotvení: -; Object Layer Attributes #1, Součinitel prostupu tepla: 0.036; Object Layer Attributes #1, Součinitel difúzního odporu: 1; Object Layer Attributes #1, Způsob spojení vrstev: Lepený + mechanicky kotvený
MINERÁLNÍ VATA | Půdorys střechy | MINERÁLNÍ VATA 0.15 m |  | MINERÁLNÍ VATA |  | 2481HWa0000000135 | m3 | Celá stěna | Nový | Zateplovací systémy | MINERÁLNÍ VATA | no | 2481Stě0000000140 | m3 | Stěna |  | 0.15 | 6.935 | 6.935 | 1.04 | 3.45 | 1.04 | 0.518 | 2.01 | NEMSOK - Object Layer Attributes #1, Kód prvku: TI06.08.1001; Object Layer Attributes #1, Požární odolnost: A1; Systém kotvení: -; Object Layer Attributes #1, Systém kotvení: -; Object Layer Attributes #1, Součinitel prostupu tepla: 0.036; Object Layer Attributes #1, Součinitel difúzního odporu: 1; Object Layer Attributes #1, Způsob spojení vrstev: Lepený + mechanicky kotvený

# IfcWindow (265)
PartitioningType: USERDEFINED
NEMSOK - V6: 0 m; V7: 0 m; V8: 0 m; V9: 0
Name | In | OverallHeight (m) | OverallWidth (m) | PredefinedType | Dolní_hrana (m) = Horní_hrana (m) | Jednotková_cena = HeightWindowSillOutside = HeightWindowSillInside = OffsetOpeningBottom = OffsetOpeningTop = OffsetOpeningLeft = OffsetOpeningRight = Perimeter (m) | Verze programu | Označení | Plugin_Bezeichnung | Plugin_Objektname | Typ skla | Uvažované procento prosklení | Verze | Zárubeň/Rám_Typ | Zárubeň/Rám_Materiál | Zárubeň/Rám_Povrch = Křídlo_Povrch_Int. = Křídlo_Povrch_Ext. | Křídlo_Materiál | Kování_Klika_Int. | Kování_Klika_Ext. = Kování_Zámek | Kování_Závěsy | Specifikace | Allright_Stavebni_dil_ID | Jednotka | Název_objektu | GlassSurface | DeductionOpeningBottom | DeductionOpeningLeft = DeductionOpeningRight | DeductionOpeningTop | ThermalTransmittance (W/K/m2) | SmokeStop = FireExit | Height (m) | Width (m) | Area (m2)
O06 | Půdorys 1.NP | 1.8 | 1.8 | WINDOW | 0 | 0 | 2.2 | O06 | MainObject | SmartPartCompressed | Izolační trojsklo 4-18-4-18-4 Ug 0,5 | 100 | 3.0 | Dřevěný rám 92 mm | Dřevěný lepený eurohranol | Bílý lak | Dřevěný lepený eurohranol | Okenní klika | není | Celoobvodové kování s pětibodovým uzávěrem | Dvojkřídlové okno otevíravé a sklápěcí, symetricky dělené s nadsvětlíkem | 1402Obj0798449432 | Kus | Okno - objekt+SmartPart | 2.0944 | 80 | 80 | 80 | 0.8 | no | 1.8 | 1.8 | 3.24
O06 | Půdorys 1.NP | 1.8 | 1.8 | WINDOW | 0 | 0 | 2.2 | O06 | MainObject | SmartPartCompressed | Izolační trojsklo 4-18-4-18-4 Ug 0,5 | 100 | 3.0 | Dřevěný rám 92 mm | Dřevěný lepený eurohranol | Bílý lak | Dřevěný lepený eurohranol | Okenní klika | není | Celoobvodové kování s pětibodovým uzávěrem | Dvojkřídlové okno otevíravé a sklápěcí, symetricky dělené s nadsvětlíkem | 1402Obj0798449155 | Kus | Okno - objekt+SmartPart | 2.0944 | 80 | 80 | 80 | 0.8 | no | 1.8 | 1.8 | 3.24
O06 | Půdorys 1.NP | 1.8 | 1.8 | WINDOW | 0 | 0 | 2.2 | O06 | MainObject | SmartPartCompressed | Izolační trojsklo 4-18-4-18-4 Ug 0,5 | 100 | 3.0 | Dřevěný rám 92 mm | Dřevěný lepený eurohranol | Bílý lak | Dřevěný lepený eurohranol | Okenní klika | není | Celoobvodové kování s pětibodovým uzávěrem | Dvojkřídlové okno otevíravé a sklápěcí, symetricky dělené s nadsvětlíkem | 1402Obj0798449188 | Kus | Okno - objekt+SmartPart | 2.0944 | 80 | 80 | 80 | 0.8 | no | 1.8 | 1.8 | 3.24
O06 | Půdorys 1.NP | 1.8 | 1.8 | WINDOW | 0 | 0 | 2.2 | O06 | MainObject | SmartPartCompressed | Izolační trojsklo 4-18-4-18-4 Ug 0,5 | 100 | 3.0 | Dřevěný rám 92 mm | Dřevěný lepený eurohranol | Bílý lak | Dřevěný lepený eurohranol | Okenní klika | není | Celoobvodové kování s pětibodovým uzávěrem | Dvojkřídlové okno otevíravé a sklápěcí, symetricky dělené s nadsvětlíkem | 1402Obj0798449221 | Kus | Okno - objekt+SmartPart | 2.0944 | 80 | 80 | 80 | 0.8 | no | 1.8 | 1.8 | 3.24
O06 | Půdorys 1.NP | 1.8 | 1.8 | WINDOW | 0 | 0 | 2.2 | O06 | MainObject | SmartPartCompressed | Izolační trojsklo 4-18-4-18-4 Ug 0,5 | 100 | 3.0 | Dřevěný rám 92 mm | Dřevěný lepený eurohranol | Bílý lak | Dřevěný lepený eurohranol | Okenní klika | není | Celoobvodové kování s pětibodovým uzávěrem | Dvojkřídlové okno otevíravé a sklápěcí, symetricky dělené s nadsvětlíkem | 1402Obj0798449122 | Kus | Okno - objekt+SmartPart | 2.0944 | 80 | 80 | 80 | 0.8 | no | 1.8 | 1.8 | 3.24
O06 | Půdorys 1.NP | 1.8 | 1.8 | WINDOW | 0 | 0 | 2.2 | O06 | MainObject | SmartPartCompressed | Izolační trojsklo 4-18-4-18-4 Ug 0,5 | 100 | 3.0 | Dřevěný rám 92 mm | Dřevěný lepený eurohranol | Bílý lak | Dřevěný lepený eurohranol | Okenní klika | není | Celoobvodové kování s pětibodovým uzávěrem | Dvojkřídlové okno otevíravé a sklápěcí, symetricky dělené s nadsvětlíkem | 1402Obj0798449089 | Kus | Okno - objekt+SmartPart | 2.0944 | 80 | 80 | 80 | 0.8 | no | 1.8 | 1.8 | 3.24
O06 | Půdorys 1.NP | 1.8 | 1.8 | WINDOW | 0 | 0 | 2.2 | O06 | MainObject | SmartPartCompressed | Izolační trojsklo 4-18-4-18-4 Ug 0,5 | 100 | 3.0 | Dřevěný rám 92 mm | Dřevěný lepený eurohranol | Bílý lak | Dřevěný lepený eurohranol | Okenní klika | není | Celoobvodové kování s pětibodovým uzávěrem | Dvojkřídlové okno otevíravé a sklápěcí, symetricky dělené s nadsvětlíkem | 1402Obj0798449056 | Kus | Okno - objekt+SmartPart | 2.0944 | 80 | 80 | 80 | 0.8 | no | 1.8 | 1.8 | 3.24
O06 | Půdorys 1.NP | 1.8 | 1.8 | WINDOW | 0 | 0 | 2.2 | O06 | MainObject | SmartPartCompressed | Izolační trojsklo 4-18-4-18-4 Ug 0,5 | 100 | 3.0 | Dřevěný rám 92 mm | Dřevěný lepený eurohranol | Bílý lak | Dřevěný lepený eurohranol | Okenní klika | není | Celoobvodové kování s pětibodovým uzávěrem | Dvojkřídlové okno otevíravé a sklápěcí, symetricky dělené s nadsvětlíkem | 1402Obj0798449023 | Kus | Okno - objekt+SmartPart | 2.0944 | 80 | 80 | 80 | 0.8 | no | 1.8 | 1.8 | 3.24
O06 | Půdorys 1.NP | 1.8 | 1.8 | WINDOW | 0 | 0 | 2.2 | O06 | MainObject | SmartPartCompressed | Izolační trojsklo 4-18-4-18-4 Ug 0,5 | 100 | 3.0 | Dřevěný rám 92 mm | Dřevěný lepený eurohranol | Bílý lak | Dřevěný lepený eurohranol | Okenní klika | není | Celoobvodové kování s pětibodovým uzávěrem | Dvojkřídlové okno otevíravé a sklápěcí, symetricky dělené s nadsvětlíkem | 1402Obj0798448990 | Kus | Okno - objekt+SmartPart | 2.0944 | 80 | 80 | 80 | 0.8 | no | 1.8 | 1.8 | 3.24
O06 | Půdorys 1.NP | 1.8 | 1.8 | WINDOW | 0 | 0 | 2.2 | O06 | MainObject | SmartPartCompressed | Izolační trojsklo 4-18-4-18-4 Ug 0,5 | 100 | 3.0 | Dřevěný rám 92 mm | Dřevěný lepený eurohranol | Bílý lak | Dřevěný lepený eurohranol | Okenní klika | není | Celoobvodové kování s pětibodovým uzávěrem | Dvojkřídlové okno otevíravé a sklápěcí, symetricky dělené s nadsvětlíkem | 1402Obj0798448956 | Kus | Okno - objekt+SmartPart | 2.0944 | 80 | 80 | 80 | 0.8 | no | 1.8 | 1.8 | 3.24
O06 | Půdorys 1.NP | 1.8 | 1.8 | WINDOW | 0 | 0 | 2.2 | O06 | MainObject | SmartPartCompressed | Izolační trojsklo 4-18-4-18-4 Ug 0,5 | 100 | 3.0 | Dřevěný rám 92 mm | Dřevěný lepený eurohranol | Bílý lak | Dřevěný lepený eurohranol | Okenní klika | není | Celoobvodové kování s pětibodovým uzávěrem | Dvojkřídlové okno otevíravé a sklápěcí, symetricky dělené s nadsvětlíkem | 1402Obj0798438697 | Kus | Okno - objekt+SmartPart | 2.0944 | 80 | 80 | 80 | 0.8 | no | 1.8 | 1.8 | 3.24
O06 | Půdorys 1.NP | 1.8 | 0.9 | WINDOW | 0 | 0 | 2.2 | O06 | MainObject | SmartPartCompressed | Izolační trojsklo 4-18-4-18-4 Ug 0,5 | 100 | 3.0 | Dřevěný rám 92 mm | Dřevěný lepený eurohranol | Bílý lak | Dřevěný lepený eurohranol | Okenní klika | není | Celoobvodové kování s pětibodovým uzávěrem | Dvojkřídlové okno otevíravé a sklápěcí, symetricky dělené s nadsvětlíkem | 1402Obj0798462493 | Kus | Okno - objekt+SmartPart | 0.9856 | 80 | 80 | 80 | 0.8 | no | 1.8 | 0.9 | 1.62
O06 | Půdorys 1.NP | 1.8 | 0.9 | WINDOW | 0 | 0 | 2.2 | O06 | MainObject | SmartPartCompressed | Izolační trojsklo 4-18-4-18-4 Ug 0,5 | 100 | 3.0 | Dřevěný rám 92 mm | Dřevěný lepený eurohranol | Bílý lak | Dřevěný lepený eurohranol | Okenní klika | není | Celoobvodové kování s pětibodovým uzávěrem | Dvojkřídlové okno otevíravé a sklápěcí, symetricky dělené s nadsvětlíkem | 1402Obj0798462636 | Kus | Okno - objekt+SmartPart | 0.9856 | 80 | 80 | 80 | 0.8 | no | 1.8 | 0.9 | 1.62
O06 | Půdorys 1.NP | 1.8 | 0.9 | WINDOW | 0 | 0 | 2.2 | O06 | MainObject | SmartPartCompressed | Izolační trojsklo 4-18-4-18-4 Ug 0,5 | 100 | 3.0 | Dřevěný rám 92 mm | Dřevěný lepený eurohranol | Bílý lak | Dřevěný lepený eurohranol | Okenní klika | není | Celoobvodové kování s pětibodovým uzávěrem | Dvojkřídlové okno otevíravé a sklápěcí, symetricky dělené s nadsvětlíkem | 1402Obj0798462664 | Kus | Okno - objekt+SmartPart | 0.9856 | 80 | 80 | 80 | 0.8 | no | 1.8 | 0.9 | 1.62
O06 | Půdorys 1.NP | 1.8 | 0.9 | WINDOW | 0 | 0 | 2.2 | O06 | MainObject | SmartPartCompressed | Izolační trojsklo 4-18-4-18-4 Ug 0,5 | 100 | 3.0 | Dřevěný rám 92 mm | Dřevěný lepený eurohranol | Bílý lak | Dřevěný lepený eurohranol | Okenní klika | není | Celoobvodové kování s pětibodovým uzávěrem | Dvojkřídlové okno otevíravé a sklápěcí, symetricky dělené s nadsvětlíkem | 1402Obj0798462690 | Kus | Okno - objekt+SmartPart | 0.9856 | 80 | 80 | 80 | 0.8 | no | 1.8 | 0.9 | 1.62
O06 | Půdorys 1.NP | 1.8 | 0.6 | WINDOW | 0 | 0 | 2.2 | O06 | MainObject | SmartPartCompressed | Izolační trojsklo 4-18-4-18-4 Ug 0,5 | 100 | 3.0 | Dřevěný rám 92 mm | Dřevěný lepený eurohranol | Bílý lak | Dřevěný lepený eurohranol | Okenní klika | není | Celoobvodové kování s pětibodovým uzávěrem | Dvojkřídlové okno otevíravé a sklápěcí, symetricky dělené s nadsvětlíkem | 1402Obj0798438518 | Kus | Okno - objekt+SmartPart | 0.5236 | 80 | 80 | 80 | 0.8 | no | 1.8 | 0.6 | 1.08
O06 | Půdorys 1.NP | 1.8 | 1.8 | WINDOW | 0 | 0 | 2.2 | O06 | MainObject | SmartPartCompressed | Izolační trojsklo 4-18-4-18-4 Ug 0,5 | 100 | 3.0 | Dřevěný rám 92 mm | Dřevěný lepený eurohranol | Bílý lak | Dřevěný lepený eurohranol | Okenní klika | není | Celoobvodové kování s pětibodovým uzávěrem | Dvojkřídlové okno otevíravé a sklápěcí, symetricky dělené s nadsvětlíkem | 1402Obj0798460872 | Kus | Okno - objekt+SmartPart | 2.0944 | 80 | 80 | 80 | 0.8 | no | 1.8 | 1.8 | 3.24
O06 | Půdorys 1.NP | 1.8 | 1.8 | WINDOW | 0 | 0 | 2.2 | O06 | MainObject | SmartPartCompressed | Izolační trojsklo 4-18-4-18-4 Ug 0,5 | 100 | 3.0 | Dřevěný rám 92 mm | Dřevěný lepený eurohranol | Bílý lak | Dřevěný lepený eurohranol | Okenní klika | není | Celoobvodové kování s pětibodovým uzávěrem | Dvojkřídlové okno otevíravé a sklápěcí, symetricky dělené s nadsvětlíkem | 1402Obj0798460870 | Kus | Okno - objekt+SmartPart | 2.0944 | 80 | 80 | 80 | 0.8 | no | 1.8 | 1.8 | 3.24
O06 | Půdorys 1.NP | 1.8 | 1.8 | WINDOW | 0 | 0 | 2.2 | O06 | MainObject | SmartPartCompressed | Izolační trojsklo 4-18-4-18-4 Ug 0,5 | 100 | 3.0 | Dřevěný rám 92 mm | Dřevěný lepený eurohranol | Bílý lak | Dřevěný lepený eurohranol | Okenní klika | není | Celoobvodové kování s pětibodovým uzávěrem | Dvojkřídlové okno otevíravé a sklápěcí, symetricky dělené s nadsvětlíkem | 1402Obj0798460868 | Kus | Okno - objekt+SmartPart | 2.0944 | 80 | 80 | 80 | 0.8 | no | 1.8 | 1.8 | 3.24
O06 | Půdorys 1.NP | 1.8 | 1.8 | WINDOW | 0 | 0 | 2.2 | O06 | MainObject | SmartPartCompressed | Izolační trojsklo 4-18-4-18-4 Ug 0,5 | 100 | 3.0 | Dřevěný rám 92 mm | Dřevěný lepený eurohranol | Bílý lak | Dřevěný lepený eurohranol | Okenní klika | není | Celoobvodové kování s pětibodovým uzávěrem | Dvojkřídlové okno otevíravé a sklápěcí, symetricky dělené s nadsvětlíkem | 1402Obj0798460866 | Kus | Okno - objekt+SmartPart | 2.0944 | 80 | 80 | 80 | 0.8 | no | 1.8 | 1.8 | 3.24
O06 | Půdorys 1.NP | 1.8 | 1.8 | WINDOW | 0 | 0 | 2.2 | O06 | MainObject | SmartPartCompressed | Izolační trojsklo 4-18-4-18-4 Ug 0,5 | 100 | 3.0 | Dřevěný rám 92 mm | Dřevěný lepený eurohranol | Bílý lak | Dřevěný lepený eurohranol | Okenní klika | není | Celoobvodové kování s pětibodovým uzávěrem | Dvojkřídlové okno otevíravé a sklápěcí, symetricky dělené s nadsvětlíkem | 1402Obj0798460864 | Kus | Okno - objekt+SmartPart | 2.0944 | 80 | 80 | 80 | 0.8 | no | 1.8 | 1.8 | 3.24
O06 | Půdorys 2.NP | 1.8 | 1.8 | WINDOW | 0 | 0 | 2.2 | O06 | MainObject | SmartPartCompressed | Izolační trojsklo 4-18-4-18-4 Ug 0,5 | 100 | 3.0 | Dřevěný rám 92 mm | Dřevěný lepený eurohranol | Bílý lak | Dřevěný lepený eurohranol | Okenní klika | není | Celoobvodové kování s pětibodovým uzávěrem | Dvojkřídlové okno otevíravé a sklápěcí, symetricky dělené s nadsvětlíkem | 1502Obj0000004165 | Kus | Okno - objekt+SmartPart | 2.0944 | 80 | 80 | 80 | 0.8 | no | 1.8 | 1.8 | 3.24
O06 | Půdorys 2.NP | 1.8 | 1.8 | WINDOW | 0 | 0 | 2.2 | O06 | MainObject | SmartPartCompressed | Izolační trojsklo 4-18-4-18-4 Ug 0,5 | 100 | 3.0 | Dřevěný rám 92 mm | Dřevěný lepený eurohranol | Bílý lak | Dřevěný lepený eurohranol | Okenní klika | není | Celoobvodové kování s pětibodovým uzávěrem | Dvojkřídlové okno otevíravé a sklápěcí, symetricky dělené s nadsvětlíkem | 1502Obj0000004201 | Kus | Okno - objekt+SmartPart | 2.0944 | 80 | 80 | 80 | 0.8 | no | 1.8 | 1.8 | 3.24
O06 | Půdorys 2.NP | 1.8 | 1.8 | WINDOW | 0 | 0 | 2.2 | O06 | MainObject | SmartPartCompressed | Izolační trojsklo 4-18-4-18-4 Ug 0,5 | 100 | 3.0 | Dřevěný rám 92 mm | Dřevěný lepený eurohranol | Bílý lak | Dřevěný lepený eurohranol | Okenní klika | není | Celoobvodové kování s pětibodovým uzávěrem | Dvojkřídlové okno otevíravé a sklápěcí, symetricky dělené s nadsvětlíkem | 1502Obj0000004234 | Kus | Okno - objekt+SmartPart | 2.0944 | 80 | 80 | 80 | 0.8 | no | 1.8 | 1.8 | 3.24
O06 | Půdorys 2.NP | 1.8 | 1.8 | WINDOW | 0 | 0 | 2.2 | O06 | MainObject | SmartPartCompressed | Izolační trojsklo 4-18-4-18-4 Ug 0,5 | 100 | 3.0 | Dřevěný rám 92 mm | Dřevěný lepený eurohranol | Bílý lak | Dřevěný lepený eurohranol | Okenní klika | není | Celoobvodové kování s pětibodovým uzávěrem | Dvojkřídlové okno otevíravé a sklápěcí, symetricky dělené s nadsvětlíkem | 1502Obj0000004627 | Kus | Okno - objekt+SmartPart | 2.0944 | 80 | 80 | 80 | 0.8 | no | 1.8 | 1.8 | 3.24
O06 | Půdorys 2.NP | 1.8 | 1.8 | WINDOW | 0 | 0 | 2.2 | O06 | MainObject | SmartPartCompressed | Izolační trojsklo 4-18-4-18-4 Ug 0,5 | 100 | 3.0 | Dřevěný rám 92 mm | Dřevěný lepený eurohranol | Bílý lak | Dřevěný lepený eurohranol | Okenní klika | není | Celoobvodové kování s pětibodovým uzávěrem | Dvojkřídlové okno otevíravé a sklápěcí, symetricky dělené s nadsvětlíkem | 1502Obj0000000291 | Kus | Okno - objekt+SmartPart | 2.0944 | 80 | 80 | 80 | 0.8 | no | 1.8 | 1.8 | 3.24
O06 | Půdorys 2.NP | 1.8 | 1.8 | WINDOW | 0 | 0 | 2.2 | O06 | MainObject | SmartPartCompressed | Izolační trojsklo 4-18-4-18-4 Ug 0,5 | 100 | 3.0 | Dřevěný rám 92 mm | Dřevěný lepený eurohranol | Bílý lak | Dřevěný lepený eurohranol | Okenní klika | není | Celoobvodové kování s pětibodovým uzávěrem | Dvojkřídlové okno otevíravé a sklápěcí, symetricky dělené s nadsvětlíkem | 1502Obj0000005983 | Kus | Okno - objekt+SmartPart | 2.0944 | 80 | 80 | 80 | 0.8 | no | 1.8 | 1.8 | 3.24
O06 | Půdorys 2.NP | 1.8 | 1.8 | WINDOW | 0 | 0 | 2.2 | O06 | MainObject | SmartPartCompressed | Izolační trojsklo 4-18-4-18-4 Ug 0,5 | 100 | 3.0 | Dřevěný rám 92 mm | Dřevěný lepený eurohranol | Bílý lak | Dřevěný lepený eurohranol | Okenní klika | není | Celoobvodové kování s pětibodovým uzávěrem | Dvojkřídlové okno otevíravé a sklápěcí, symetricky dělené s nadsvětlíkem | 1502Obj0000004410 | Kus | Okno - objekt+SmartPart | 2.0944 | 80 | 80 | 80 | 0.8 | no | 1.8 | 1.8 | 3.24
O06 | Půdorys 2.NP | 1.8 | 1.8 | WINDOW | 0 | 0 | 2.2 | O06 | MainObject | SmartPartCompressed | Izolační trojsklo 4-18-4-18-4 Ug 0,5 | 100 | 3.0 | Dřevěný rám 92 mm | Dřevěný lepený eurohranol | Bílý lak | Dřevěný lepený eurohranol | Okenní klika | není | Celoobvodové kování s pětibodovým uzávěrem | Dvojkřídlové okno otevíravé a sklápěcí, symetricky dělené s nadsvětlíkem | 1502Obj0000004533 | Kus | Okno - objekt+SmartPart | 2.0944 | 80 | 80 | 80 | 0.8 | no | 1.8 | 1.8 | 3.24
O06 | Půdorys 1.PP | 1.5 | 1.5 | WINDOW | 0 | 0 | 2.2 | O06 | MainObject | SmartPartCompressed | Izolační zasklení | 100 | 3.0 | Dřevěný rám | Dřevo | Bílý lak | Dřevo | Okenní klika | není | nezadáno | Jednokřídlové kyvné | 1352Obj0798472294 | Kus | Okno - objekt+SmartPart | 1.5376 | 80 | 80 | 80 | 0.8 | no | 1.5 | 1.5 | 2.25 | Pset_WindowCommon - Status: DEMOLISH
O06 | Půdorys 1.PP | 1.5 | 1.5 | WINDOW | 0 | 0 | 2.2 | O06 | MainObject | SmartPartCompressed | Izolační zasklení | 100 | 3.0 | Dřevěný rám | Dřevo | Bílý lak | Dřevo | Okenní klika | není | nezadáno | Jednokřídlové kyvné | 1352Obj0798472443 | Kus | Okno - objekt+SmartPart | 1.5376 | 80 | 80 | 80 | 0.8 | no | 1.5 | 1.5 | 2.25 | Pset_WindowCommon - Status: DEMOLISH
O06 | Půdorys 1.PP | 1.5 | 1.5 | WINDOW | 0 | 0 | 2.2 | O06 | MainObject | SmartPartCompressed | Izolační zasklení | 100 | 3.0 | Dřevěný rám | Dřevo | Bílý lak | Dřevo | Okenní klika | není | nezadáno | Jednokřídlové kyvné | 1352Obj0798472472 | Kus | Okno - objekt+SmartPart | 1.5376 | 80 | 80 | 80 | 0.8 | no | 1.5 | 1.5 | 2.25 | Pset_WindowCommon - Status: DEMOLISH
O01 | Půdorys 1.PP | 1.2 | 0.4 | WINDOW | 0 | 0 | 2.2 | O01 | MainObject | SmartPartCompressed |  | 100 | 3.0 | Dřevěný rám 92 mm | Dřevěný lepený eurohranol | Bílý lak | Dřevěný lepený eurohranol | Okenní klika | není | Celoobvodové kování s pětibodovým uzávěrem |  | 1352Obj0798469325 | Kus | Okno - objekt+SmartPart | 0 | 20 | 20 | 20 | 0.8 | no | 1.2 | 0.4 | 0.48
O01 | Půdorys 1.PP | 1.2 | 0.6 | WINDOW | 0 | 0 | 2.2 | O01 | MainObject | SmartPartCompressed |  | 100 | 3.0 | Dřevěný rám 92 mm | Dřevěný lepený eurohranol | Bílý lak | Dřevěný lepený eurohranol | Okenní klika | není | Celoobvodové kování s pětibodovým uzávěrem |  | 1352Obj0798460674 | Kus | Okno - objekt+SmartPart | 0 | 20 | 20 | 20 | 0.8 | no | 1.2 | 0.6 | 0.72
O01 | Půdorys 1.PP | 1.2 | 0.4 | WINDOW | 0 | 0 | 2.2 | O01 | MainObject | SmartPartCompressed |  | 100 | 3.0 | Dřevěný rám 92 mm | Dřevěný lepený eurohranol | Bílý lak | Dřevěný lepený eurohranol | Okenní klika | není | Celoobvodové kování s pětibodovým uzávěrem |  | 1352Obj0798469362 | Kus | Okno - objekt+SmartPart | 0 | 20 | 20 | 20 | 0.8 | no | 1.2 | 0.4 | 0.48
O01 | Půdorys 1.PP | 1.2 | 0.6 | WINDOW | 0 | 0 | 2.2 | O01 | MainObject | SmartPartCompressed |  | 100 | 3.0 | Dřevěný rám 92 mm | Dřevěný lepený eurohranol | Bílý lak | Dřevěný lepený eurohranol | Okenní klika | není | Celoobvodové kování s pětibodovým uzávěrem |  | 1352Obj0798470407 | Kus | Okno - objekt+SmartPart | 0 | 20 | 20 | 20 | 0.8 | no | 1.2 | 0.6 | 0.72 | Pset_WindowCommon - Status: DEMOLISH
O01 | Půdorys 1.PP | 1.2 | 0.6 | WINDOW | 0 | 0 | 2.2 | O01 | MainObject | SmartPartCompressed |  | 100 | 3.0 | Dřevěný rám 92 mm | Dřevěný lepený eurohranol | Bílý lak | Dřevěný lepený eurohranol | Okenní klika | není | Celoobvodové kování s pětibodovým uzávěrem |  | 1352Obj0798471181 | Kus | Okno - objekt+SmartPart | 0 | 20 | 20 | 20 | 0.8 | no | 1.2 | 0.6 | 0.72 | Pset_WindowCommon - Status: DEMOLISH
O01 | Půdorys 1.PP | 1.2 | 0.6 | WINDOW | 0 | 0 | 2.2 | O01 | MainObject | SmartPartCompressed |  | 100 | 3.0 | Dřevěný rám 92 mm | Dřevěný lepený eurohranol | Bílý lak | Dřevěný lepený eurohranol | Okenní klika | není | Celoobvodové kování s pětibodovým uzávěrem |  | 1352Obj0798500088 | Kus | Okno - objekt+SmartPart | 0 | 20 | 20 | 20 | 0.8 | no | 1.2 | 0.6 | 0.72 | Pset_WindowCommon - Status: DEMOLISH
O01 | Půdorys 1.PP | 0.3 | 0.3 | WINDOW | 0 | 0 | 2.2 | O01 | MainObject | SmartPartCompressed |  | 100 | 3.0 | Dřevěný rám 92 mm | Dřevěný lepený eurohranol | Bílý lak | Dřevěný lepený eurohranol | Okenní klika | není | Celoobvodové kování s pětibodovým uzávěrem |  | 1352Obj0798494332 | Kus | Okno - objekt+SmartPart | 0 | 20 | 20 | 20 | 0.8 | no | 0.3 | 0.3 | 0.09
O01 | Půdorys 1.PP | 1.2 | 1.0875 | WINDOW | 0 | 0 | 2.2 | O01 | MainObject | SmartPartCompressed |  | 100 | 3.0 | Dřevěný rám 92 mm | Dřevěný lepený eurohranol | Bílý lak | Dřevěný lepený eurohranol | Okenní klika | není | Celoobvodové kování s pětibodovým uzávěrem |  | 1352Obj0798496908 | Kus | Okno - objekt+SmartPart | 0 | 20 | 20 | 20 | 0.8 | no | 1.2 | 1.088 | 1.305 | Pset_WindowCommon - Status: DEMOLISH
O01 | Půdorys 1.PP | 1.2 | 0.55 | WINDOW | 0 | 0 | 2.2 | O01 | MainObject | SmartPartCompressed |  | 100 | 3.0 | Dřevěný rám 92 mm | Dřevěný lepený eurohranol | Bílý lak | Dřevěný lepený eurohranol | Okenní klika | není | Celoobvodové kování s pětibodovým uzávěrem |  | 1352Obj0798498659 | Kus | Okno - objekt+SmartPart | 0 | 20 | 20 | 20 | 0.8 | no | 1.2 | 0.55 | 0.66 | Pset_WindowCommon - Status: DEMOLISH
O01 | Půdorys 1.PP | 1.2 | 0.6 | WINDOW | 0 | 0 | 2.2 | O01 | MainObject | SmartPartCompressed |  | 100 | 3.0 | Dřevěný rám 92 mm | Dřevěný lepený eurohranol | Bílý lak | Dřevěný lepený eurohranol | Okenní klika | není | Celoobvodové kování s pětibodovým uzávěrem |  | 1352Obj0798498601 | Kus | Okno - objekt+SmartPart | 0 | 20 | 20 | 20 | 0.8 | no | 1.2 | 0.6 | 0.72 | Pset_WindowCommon - Status: DEMOLISH
O01 | Půdorys 1.PP | 1.2 | 0.6 | WINDOW | 0 | 0 | 2.2 | O01 | MainObject | SmartPartCompressed |  | 100 | 3.0 | Dřevěný rám 92 mm | Dřevěný lepený eurohranol | Bílý lak | Dřevěný lepený eurohranol | Okenní klika | není | Celoobvodové kování s pětibodovým uzávěrem |  | 1352Obj0798496649 | Kus | Okno - objekt+SmartPart | 0 | 20 | 20 | 20 | 0.8 | no | 1.2 | 0.6 | 0.72 | Pset_WindowCommon - Status: DEMOLISH
O01 | Půdorys 1.PP | 1.2 | 0.6 | WINDOW | 0 | 0 | 2.2 | O01 | MainObject | SmartPartCompressed |  | 100 | 3.0 | Dřevěný rám 92 mm | Dřevěný lepený eurohranol | Bílý lak | Dřevěný lepený eurohranol | Okenní klika | není | Celoobvodové kování s pětibodovým uzávěrem |  | 1352Obj0798496660 | Kus | Okno - objekt+SmartPart | 0 | 20 | 20 | 20 | 0.8 | no | 1.2 | 0.6 | 0.72 | Pset_WindowCommon - Status: DEMOLISH
I.OP06 | Půdorys 1.PP | 1.2 | 1.5 | WINDOW |  | 0 | 2.2 | I.OP06 | MainObject | SmartPartCompressed | Izolační trojsklo 4-18-4-18-4 | 100 | 3.0 | Plastový profil 82mm | Plastový profil | Barva bílá | Plastový profil | Okenní klika | není | Celoobvodové kování s pětibodovým uzávěrem | Dvojkřídlové okno, 2×otevíravé | 1364Obj0798520609 | Kus | Okno - objekt+SmartPart | 1.07066 | 80 | 80 | 80 | 0.8 | no | 1.2 | 1.5 | 1.8 | Pset_WindowCommon - Status: NEW; SecurityRating: bez; NEMSOK - Kód prvku: ON04.02.0008; Podlaží: 1.PP; Součinitel prostupu tepla - zasklení (Ug): Ug 0,6; Typ otevírání: Dvojkřídlové okno, 2×otevíravé; Solární faktor: 0.52; Světelný činitel prostupu: 0.74; Průvzdušnost: 4; Zasklení: Izolační trojsklo 4-18-4-18-4; Připojení EZS: Ano; Připojení NN: Ne; Připojení EPS: Ne; Připojení MaR: Ne; Vnitřní parapet - materiál: Vlhkuodolná DTD
I.OP05 | Půdorys 1.PP | 1.2 | 1.5 | WINDOW |  | 0 | 2.2 | I.OP05 | MainObject | SmartPartCompressed | Izolační trojsklo 4-18-4-18-4 | 100 | 3.0 | Plastový profil 82mm | Plastový profil | Barva bílá | Plastový profil | Okenní klika | není | Celoobvodové kování s pětibodovým uzávěrem | Dvojkřídlové okno, 2×otevíravé | 1364Obj0798520819 | Kus | Okno - objekt+SmartPart | 1.07066 | 80 | 80 | 80 | 0.8 | no | 1.2 | 1.5 | 1.8 | Pset_WindowCommon - Status: NEW; SecurityRating: bez; NEMSOK - Kód prvku: ON04.02.0009; Podlaží: 1.PP; Součinitel prostupu tepla - zasklení (Ug): Ug 0,6; Typ otevírání: Dvojkřídlové okno, 2×otevíravé; Solární faktor: 0.52; Světelný činitel prostupu: 0.74; Průvzdušnost: 4; Zasklení: Izolační trojsklo 4-18-4-18-4; Připojení EZS: Ano; Připojení NN: Ne; Připojení EPS: Ne; Připojení MaR: Ne; Vnitřní parapet - materiál: Vlhkuodolná DTD
I.OP05 | Půdorys 1.PP | 1.2 | 1.5 | WINDOW |  | 0 | 2.2 | I.OP05 | MainObject | SmartPartCompressed | Izolační trojsklo 4-18-4-18-4 | 100 | 3.0 | Plastový profil 82mm | Plastový profil | Barva bílá | Plastový profil | Okenní klika | není | Celoobvodové kování s pětibodovým uzávěrem | Dvojkřídlové okno, 2×otevíravé | 1364Obj0798521067 | Kus | Okno - objekt+SmartPart | 1.07066 | 80 | 80 | 80 | 0.8 | no | 1.2 | 1.5 | 1.8 | Pset_WindowCommon - Status: NEW; SecurityRating: bez; NEMSOK - Kód prvku: ON04.02.0010; Podlaží: 1.PP; Součinitel prostupu tepla - zasklení (Ug): Ug 0,6; Typ otevírání: Dvojkřídlové okno, 2×otevíravé; Solární faktor: 0.52; Světelný činitel prostupu: 0.74; Průvzdušnost: 4; Zasklení: Izolační trojsklo 4-18-4-18-4; Připojení EZS: Ano; Připojení NN: Ne; Připojení EPS: Ne; Připojení MaR: Ne; Vnitřní parapet - materiál: Vlhkuodolná DTD
I.OP10 | Půdorys 1.PP | 1.5 | 0.9 | WINDOW |  | 0 | 2.2 | I.OP10 | MainObject | SmartPartCompressed | Izolační trojsklo 4-18-4-18-4 | 100 | 3.0 | Plastový profil 82mm | Plastový profil | Barva bílá | Plastový profil | Okenní klika | není | Celoobvodové kování s pětibodovým uzávěrem | Jednokřídlové otevíravé/sklopné | 1364Obj0798493608 | Kus | Okno - objekt+SmartPart | 0.7936 | 80 | 80 | 80 | 0.8 | no | 1.5 | 0.9 | 1.35 | Pset_WindowCommon - Status: NEW; SecurityRating: bez; NEMSOK - Kód prvku: ON04.02.0004; Podlaží: 1.PP; Součinitel prostupu tepla - zasklení (Ug): Ug 0,6; Typ otevírání: Jednokřídlové otevíravé/sklopné; Solární faktor: 0.52; Světelný činitel prostupu: 0.74; Průvzdušnost: 4; Zasklení: Izolační trojsklo 4-18-4-18-4; Připojení EZS: Ano; Připojení NN: Ne; Připojení EPS: Ne; Připojení MaR: Ne; Vnitřní parapet - materiál: Vlhkuodolná DTD
I.OP09a | Půdorys 1.PP | 1.5 | 0.9 | WINDOW |  | 0 | 2.2 | I.OP09a | MainObject | SmartPartCompressed | Izolační trojsklo 4-18-4-18-4 | 100 | 3.0 | Plastový profil 82mm | Plastový profil | Barva bílá | Plastový profil | Okenní klika | není | Celoobvodové kování s pětibodovým uzávěrem | Jednokřídlové otevíravé/sklopné | 1364Obj0798508509 | Kus | Okno - objekt+SmartPart | 0.7936 | 80 | 80 | 80 | 0.8 | no | 1.5 | 0.9 | 1.35 | Pset_WindowCommon - Status: NEW; SecurityRating: bez; NEMSOK - Kód prvku: ON04.02.0007; Podlaží: 1.PP; Součinitel prostupu tepla - zasklení (Ug): Ug 0,6; Typ otevírání: Jednokřídlové otevíravé/sklopné; Solární faktor: 0.52; Světelný činitel prostupu: 0.74; Průvzdušnost: 4; Zasklení: Izolační trojsklo 4-18-4-18-4; Připojení EZS: Ano; Připojení NN: Ne; Připojení EPS: Ne; Připojení MaR: Ne; Vnitřní parapet - materiál: Vlhkuodolná DTD
I.OP02 | Půdorys 1.PP | 1.5 | 1.5 | WINDOW |  | 0 | 2.2 | I.OP02 | MainObject | SmartPartCompressed | Izolační trojsklo 4-18-4-18-4 | 100 | 3.0 | Plastový profil 82mm | Plastový profil | Barva bílá | Plastový profil | Okenní klika | není | Celoobvodové kování s pětibodovým uzávěrem | Dvojkřídlové okno, 1×otevíravé/sklopné, 1×otevíravé | 1364Obj0798606580 | Kus | Okno - objekt+SmartPart | 1.41236 | 80 | 80 | 80 | 0.8 | no | 1.5 | 1.5 | 2.25 | Pset_WindowCommon - Status: NEW; SecurityRating: bez; NEMSOK - Kód prvku: ON04.02.0011; Podlaží: 1.PP; Součinitel prostupu tepla - zasklení (Ug): Ug 0,6; Typ otevírání: Dvojkřídlové okno, 1×otevíravé/sklopné, 1×otevíravé; Solární faktor: 0.52; Světelný činitel prostupu: 0.74; Průvzdušnost: 4; Zasklení: Izolační trojsklo 4-18-4-18-4; Připojení EZS: Ano; Připojení NN: Ne; Připojení EPS: Ne; Připojení MaR: Ne; Vnitřní parapet - materiál: Vlhkuodolná DTD
I.OP04 | Půdorys 1.PP | 1.5 | 1.5 | WINDOW |  | 0 | 2.2 | I.OP04 | MainObject | SmartPartCompressed | Izolační trojsklo 4-18-4-18-4 | 100 | 3.0 | Plastový profil 82mm | Plastový profil | Barva bílá | Plastový profil | Okenní klika | není | Celoobvodové kování s pětibodovým uzávěrem | Dvojkřídlové okno, 1×otevíravé/sklopné, 1×otevíravé | 1364Obj0798606798 | Kus | Okno - objekt+SmartPart | 1.41236 | 80 | 80 | 80 | 0.8 | no | 1.5 | 1.5 | 2.25 | Pset_WindowCommon - Status: NEW; SecurityRating: bez; NEMSOK - Kód prvku: ON04.02.0014; Podlaží: 1.PP; Součinitel prostupu tepla - zasklení (Ug): Ug 0,6; Typ otevírání: Dvojkřídlové okno, 1×otevíravé/sklopné, 1×otevíravé; Solární faktor: 0.52; Světelný činitel prostupu: 0.74; Průvzdušnost: 4; Zasklení: Izolační trojsklo 4-18-4-18-4; Připojení EZS: Ano; Připojení NN: Ne; Připojení EPS: Ne; Připojení MaR: Ne; Vnitřní parapet - materiál: Vlhkuodolná DTD
I.OP03 | Půdorys 1.PP | 1.5 | 1.5 | WINDOW |  | 0 | 2.2 | I.OP03 | MainObject | SmartPartCompressed | Izolační trojsklo 4-18-4-18-4 | 100 | 3.0 | Plastový profil 82mm | Plastový profil | Barva bílá | Plastový profil | Okenní klika | není | Celoobvodové kování s pětibodovým uzávěrem | Dvojkřídlové okno, 1×otevíravé/sklopné, 1×otevíravé | 1364Obj0798606765 | Kus | Okno - objekt+SmartPart | 1.41236 | 80 | 80 | 80 | 0.8 | no | 1.5 | 1.5 | 2.25 | Pset_WindowCommon - Status: NEW; SecurityRating: bez; NEMSOK - Kód prvku: ON04.02.0013; Podlaží: 1.PP; Součinitel prostupu tepla - zasklení (Ug): Ug 0,6; Typ otevírání: Dvojkřídlové okno, 1×otevíravé/sklopné, 1×otevíravé; Solární faktor: 0.52; Světelný činitel prostupu: 0.74; Průvzdušnost: 4; Zasklení: Izolační trojsklo 4-18-4-18-4; Připojení EZS: Ano; Připojení NN: Ne; Připojení EPS: Ne; Připojení MaR: Ne; Vnitřní parapet - materiál: Vlhkuodolná DTD
I.OP04 | Půdorys 1.PP | 1.5 | 1.5 | WINDOW |  | 0 | 2.2 | I.OP04 | MainObject | SmartPartCompressed | Izolační trojsklo 4-18-4-18-4 | 100 | 3.0 | Plastový profil 82mm | Plastový profil | Barva bílá | Plastový profil | Okenní klika | není | Celoobvodové kování s pětibodovým uzávěrem | Dvojkřídlové okno, 1×otevíravé/sklopné, 1×otevíravé | 1364Obj0798606731 | Kus | Okno - objekt+SmartPart | 1.41236 | 80 | 80 | 80 | 0.8 | no | 1.5 | 1.5 | 2.25 | Pset_WindowCommon - Status: NEW; SecurityRating: bez; NEMSOK - Kód prvku: ON04.02.0012; Podlaží: 1.PP; Součinitel prostupu tepla - zasklení (Ug): Ug 0,6; Typ otevírání: Dvojkřídlové okno, 1×otevíravé/sklopné, 1×otevíravé; Solární faktor: 0.52; Světelný činitel prostupu: 0.74; Průvzdušnost: 4; Zasklení: Izolační trojsklo 4-18-4-18-4; Připojení EZS: Ano; Připojení NN: Ne; Připojení EPS: Ne; Připojení MaR: Ne; Vnitřní parapet - materiál: Vlhkuodolná DTD
I.OP04 | Půdorys 1.PP | 1.5 | 1.5 | WINDOW |  | 0 | 2.2 | I.OP04 | MainObject | SmartPartCompressed | Izolační trojsklo 4-18-4-18-4 | 100 | 3.0 | Plastový profil 82mm | Plastový profil | Barva bílá | Plastový profil | Okenní klika | není | Celoobvodové kování s pětibodovým uzávěrem | Dvojkřídlové okno, 1×otevíravé/sklopné, 1×otevíravé | 1364Obj0798606957 | Kus | Okno - objekt+SmartPart | 1.41236 | 80 | 80 | 80 | 0.8 | no | 1.5 | 1.5 | 2.25 | Pset_WindowCommon - Status: NEW; SecurityRating: bez; NEMSOK - Kód prvku: ON04.02.0015; Podlaží: 1.PP; Součinitel prostupu tepla - zasklení (Ug): Ug 0,6; Typ otevírání: Dvojkřídlové okno, 1×otevíravé/sklopné, 1×otevíravé; Solární faktor: 0.52; Světelný činitel prostupu: 0.74; Průvzdušnost: 4; Zasklení: Izolační trojsklo 4-18-4-18-4; Připojení EZS: Ano; Připojení NN: Ne; Připojení EPS: Ne; Připojení MaR: Ne; Vnitřní parapet - materiál: Vlhkuodolná DTD
I.OP01 | Půdorys 1.PP | 1.5 | 1.5 | WINDOW |  | 0 | 2.2 | I.OP01 | MainObject | SmartPartCompressed | Izolační trojsklo 4-18-4-18-4 | 100 | 3.0 | Plastový profil 82mm | Plastový profil | Barva bílá | Plastový profil | Okenní klika | není | Celoobvodové kování s pětibodovým uzávěrem | Dvojkřídlové okno, 1×otevíravé/sklopné, 1×otevíravé | 1364Obj0798495824 | Kus | Okno - objekt+SmartPart | 1.41236 | 80 | 80 | 80 | 0.8 | no | 1.5 | 1.5 | 2.25 | Pset_WindowCommon - Status: NEW; SecurityRating: bez; NEMSOK - Kód prvku: ON04.02.0005; Podlaží: 1.PP; Součinitel prostupu tepla - zasklení (Ug): Ug 0,6; Typ otevírání: Dvojkřídlové okno, 1×otevíravé/sklopné, 1×otevíravé; Solární faktor: 0.52; Světelný činitel prostupu: 0.74; Průvzdušnost: 4; Zasklení: Izolační trojsklo 4-18-4-18-4; Připojení EZS: Ano; Připojení NN: Ne; Připojení EPS: Ne; Připojení MaR: Ne; Vnitřní parapet - materiál: Vlhkuodolná DTD
I.OP01 | Půdorys 1.PP | 1.5 | 1.5 | WINDOW |  | 0 | 2.2 | I.OP01 | MainObject | SmartPartCompressed | Izolační trojsklo 4-18-4-18-4 | 100 | 3.0 | Plastový profil 82mm | Plastový profil | Barva bílá | Plastový profil | Okenní klika | není | Celoobvodové kování s pětibodovým uzávěrem | Dvojkřídlové okno, 1×otevíravé/sklopné, 1×otevíravé | 1364Obj0798495882 | Kus | Okno - objekt+SmartPart | 1.41236 | 80 | 80 | 80 | 0.8 | no | 1.5 | 1.5 | 2.25 | Pset_WindowCommon - Status: NEW; SecurityRating: bez; NEMSOK - Kód prvku: ON04.02.0006; Podlaží: 1.PP; Součinitel prostupu tepla - zasklení (Ug): Ug 0,6; Typ otevírání: Dvojkřídlové okno, 1×otevíravé/sklopné, 1×otevíravé; Solární faktor: 0.52; Světelný činitel prostupu: 0.74; Průvzdušnost: 4; Zasklení: Izolační trojsklo 4-18-4-18-4; Připojení EZS: Ano; Připojení NN: Ne; Připojení EPS: Ne; Připojení MaR: Ne; Vnitřní parapet - materiál: Vlhkuodolná DTD
I.OP09b | Půdorys 1.PP | 1.5 | 0.9 | WINDOW |  | 0 | 2.2 | I.OP09b | MainObject | SmartPartCompressed | Izolační trojsklo 4-18-4-18-4 | 100 | 3.0 | Plastový profil 82mm | Plastový profil | Barva bílá | Plastový profil | Okenní klika | není | Celoobvodové kování s pětibodovým uzávěrem | Jednokřídlové otevíravé/sklopné | 1364Obj0798607282 | Kus | Okno - objekt+SmartPart | 0.7936 | 80 | 80 | 80 | 0.8 | no | 1.5 | 0.9 | 1.35 | Pset_WindowCommon - Status: NEW; SecurityRating: bez; NEMSOK - Kód prvku: ON04.02.0001; Podlaží: 1.PP; Součinitel prostupu tepla - zasklení (Ug): 0; Typ otevírání: Jednokřídlové otevíravé/sklopné; Solární faktor: 0.52; Světelný činitel prostupu: 0.74; Průvzdušnost: 4; Zasklení: Izolační trojsklo 4-18-4-18-4; Připojení EZS: Ano; Připojení NN: Ne; Připojení EPS: Ne; Připojení MaR: Ne; Vnitřní parapet - materiál: Vlhkuodolná DTD
I.OP07 | Půdorys 1.PP | 1.5 | 0.9 | WINDOW |  | 0 | 2.2 | I.OP07 | MainObject | SmartPartCompressed | Izolační trojsklo 4-18-4-18-4 | 100 | 3.0 | Plastový profil 82mm | Plastový profil | Barva bílá | Plastový profil | Okenní klika | není | Celoobvodové kování s pětibodovým uzávěrem | Jednokřídlové otevíravé/sklopné | 1364Obj0798607348 | Kus | Okno - objekt+SmartPart | 0.7936 | 80 | 80 | 80 | 0.8 | no | 1.5 | 0.9 | 1.35 | Pset_WindowCommon - Status: NEW; SecurityRating: bez; NEMSOK - Kód prvku: ON04.02.0002; Podlaží: 1.PP; Součinitel prostupu tepla - zasklení (Ug): 0; Typ otevírání: Jednokřídlové otevíravé/sklopné; Solární faktor: 0.52; Světelný činitel prostupu: 0.74; Průvzdušnost: 4; Zasklení: Izolační trojsklo 4-18-4-18-4; Připojení EZS: Ano; Připojení NN: Ne; Připojení EPS: Ne; Připojení MaR: Ne; Vnitřní parapet - materiál: Vlhkuodolná DTD
I.OP08 | Půdorys 1.PP | 1.5 | 0.9 | WINDOW |  | 0 | 2.2 | I.OP08 | MainObject | SmartPartCompressed | Izolační trojsklo 4-18-4-18-4 | 100 | 3.0 | Plastový profil 82mm | Plastový profil | Barva bílá | Plastový profil | Okenní klika | není | Celoobvodové kování s pětibodovým uzávěrem | Jednokřídlové otevíravé/sklopné | 1364Obj0798607382 | Kus | Okno - objekt+SmartPart | 0.7936 | 80 | 80 | 80 | 0.8 | no | 1.5 | 0.9 | 1.35 | Pset_WindowCommon - Status: NEW; SecurityRating: bez; NEMSOK - Kód prvku: ON04.02.0003; Podlaží: 1.PP; Součinitel prostupu tepla - zasklení (Ug): 0; Typ otevírání: Jednokřídlové otevíravé/sklopné; Solární faktor: 0.52; Světelný činitel prostupu: 0.74; Průvzdušnost: 4; Zasklení: Izolační trojsklo 4-18-4-18-4; Připojení EZS: Ano; Připojení NN: Ne; Připojení EPS: Ne; Připojení MaR: Ne; Vnitřní parapet - materiál: Keramický obklad
 | Půdorys 1.PP | 0.2 | 0.2 | WINDOW |  | 0 | 2.2 |  | MainObject | SmartPartCompressed |  | 100 | 3.0 | Ocelový rám | Ocelová | Bílý lak | Ocelové | Okenní klika | není | Celoobvodové kování s pětibodovým uzávěrem | Bemerkung mit max 254Zeichen | 1364Obj0798563235 | Kus | Okno - objekt+SmartPart | 0 | 20 | 20 | 20 | 0 | no | 0.2 | 0.2 | 0.04 | Pset_WindowCommon - SecurityRating: bez
 | Půdorys 1.PP | 0.2 | 0.2 | WINDOW |  | 0 | 2.2 |  | MainObject | SmartPartCompressed |  | 100 | 3.0 | Ocelový rám | Ocelová | Bílý lak | Ocelové | Okenní klika | není | Celoobvodové kování s pětibodovým uzávěrem | Bemerkung mit max 254Zeichen | 1364Obj0798563152 | Kus | Okno - objekt+SmartPart | 0 | 20 | 20 | 20 | 0 | no | 0.2 | 0.2 | 0.04 | Pset_WindowCommon - SecurityRating: bez
 | Půdorys 1.PP | 0.2 | 0.2 | WINDOW |  | 0 | 2.2 |  | MainObject | SmartPartCompressed |  | 100 | 3.0 | Ocelový rám | Ocelová | Bílý lak | Ocelové | Okenní klika | není | Celoobvodové kování s pětibodovým uzávěrem | Bemerkung mit max 254Zeichen | 1364Obj0798563297 | Kus | Okno - objekt+SmartPart | 0 | 20 | 20 | 20 | 0 | no | 0.2 | 0.2 | 0.04 | Pset_WindowCommon - SecurityRating: bez
 | Půdorys 1.PP | 0.4 | 0.4 | WINDOW |  | 0 | 2.2 |  | MainObject | SmartPartCompressed |  | 100 | 3.0 | Ocelový rám | Ocelová | Bílý lak | Ocelové | Okenní klika | není | Celoobvodové kování s pětibodovým uzávěrem | Bemerkung mit max 254Zeichen | 1364Obj0798562675 | Kus | Okno - objekt+SmartPart | 0 | 20 | 20 | 20 | 0 | no | 0.4 | 0.4 | 0.16 | Pset_WindowCommon - SecurityRating: bez
 | Půdorys 1.PP | 0.2 | 0.2 | WINDOW |  | 0 | 2.2 |  | MainObject | SmartPartCompressed |  | 100 | 3.0 | Ocelový rám | Ocelová | Bílý lak | Ocelové | Okenní klika | není | Celoobvodové kování s pětibodovým uzávěrem | Bemerkung mit max 254Zeichen | 1364Obj0798563284 | Kus | Okno - objekt+SmartPart | 0 | 20 | 20 | 20 | 0 | no | 0.2 | 0.2 | 0.04 | NEMSOK - Kód prvku: ZV00.02.6001; Pset_WindowCommon - SecurityRating: bez
 | Půdorys 1.PP | 0.4 | 0.4 | WINDOW |  | 0 | 2.2 |  | MainObject | SmartPartCompressed |  | 100 | 3.0 | Ocelový rám | Ocelová | Bílý lak | Ocelové | Okenní klika | není | Celoobvodové kování s pětibodovým uzávěrem | Bemerkung mit max 254Zeichen | 1364Obj0798562699 | Kus | Okno - objekt+SmartPart | 0 | 20 | 20 | 20 | 0 | no | 0.4 | 0.4 | 0.16 | NEMSOK - Kód prvku: ZV00.02.6001; Pset_WindowCommon - SecurityRating: bez
 | Půdorys 1.PP | 0.2 | 0.2 | WINDOW |  | 0 | 2.2 |  | MainObject | SmartPartCompressed |  | 100 | 3.0 | Ocelový rám | Ocelová | Bílý lak | Ocelové | Okenní klika | není | Celoobvodové kování s pětibodovým uzávěrem | Bemerkung mit max 254Zeichen | 1364Obj0798563367 | Kus | Okno - objekt+SmartPart | 0 | 20 | 20 | 20 | 0 | no | 0.2 | 0.2 | 0.04 | Pset_WindowCommon - SecurityRating: bez
 | Půdorys 1.PP | 0.4 | 0.4 | WINDOW |  | 0 | 2.2 |  | MainObject | SmartPartCompressed |  | 100 | 3.0 | Ocelový rám | Ocelová | Bílý lak | Ocelové | Okenní klika | není | Celoobvodové kování s pětibodovým uzávěrem | Bemerkung mit max 254Zeichen | 1364Obj0798562687 | Kus | Okno - objekt+SmartPart | 0 | 20 | 20 | 20 | 0 | no | 0.4 | 0.4 | 0.16 | NEMSOK - Kód prvku: ZV00.02.6001; Pset_WindowCommon - SecurityRating: bez
 | Půdorys 1.PP | 0.3 | 0.3 | WINDOW |  | 0 | 2.2 |  | MainObject | SmartPartCompressed |  | 100 | 3.0 | Ocelový rám | Ocelová | Bílý lak | Ocelové | Okenní klika | není | Celoobvodové kování s pětibodovým uzávěrem | Bemerkung mit max 254Zeichen | 1364Obj0798563513 | Kus | Okno - objekt+SmartPart | 0 | 20 | 20 | 20 | 0 | no | 0.3 | 0.3 | 0.09 | Pset_WindowCommon - SecurityRating: bez
 | Půdorys 1.PP | 0.3 | 0.3 | WINDOW |  | 0 | 2.2 |  | MainObject | SmartPartCompressed |  | 100 | 3.0 | Ocelový rám | Ocelová | Bílý lak | Ocelové | Okenní klika | není | Celoobvodové kování s pětibodovým uzávěrem | Bemerkung mit max 254Zeichen | 1364Obj0798563562 | Kus | Okno - objekt+SmartPart | 0 | 20 | 20 | 20 | 0 | no | 0.3 | 0.3 | 0.09 | NEMSOK - Kód prvku: ZV00.02.6001; Pset_WindowCommon - SecurityRating: bez
 | Půdorys 1.PP | 0.2 | 0.2 | WINDOW |  | 0 | 2.2 |  | MainObject | SmartPartCompressed |  | 100 | 3.0 | Ocelový rám | Ocelová | Bílý lak | Ocelové | Okenní klika | není | Celoobvodové kování s pětibodovým uzávěrem | Bemerkung mit max 254Zeichen | 1364Obj0798563500 | Kus | Okno - objekt+SmartPart | 0 | 20 | 20 | 20 | 0 | no | 0.2 | 0.2 | 0.04 | NEMSOK - Kód prvku: ZV00.02.6001; Pset_WindowCommon - SecurityRating: bez
 | Půdorys 1.PP | 0.3 | 0.3 | WINDOW |  | 0 | 2.2 |  | MainObject | SmartPartCompressed |  | 100 | 3.0 | Ocelový rám | Ocelová | Bílý lak | Ocelové | Okenní klika | není | Celoobvodové kování s pětibodovým uzávěrem | Bemerkung mit max 254Zeichen | 1364Obj0798563583 | Kus | Okno - objekt+SmartPart | 0 | 20 | 20 | 20 | 0 | no | 0.3 | 0.3 | 0.09 | NEMSOK - Kód prvku: ZV00.02.6001; Pset_WindowCommon - SecurityRating: bez
O06 | Půdorys 1.NP | 2.1 | 1.5 | WINDOW | 0 | 0 | 2.2 | O06 | MainObject | SmartPartCompressed | Izolační trojsklo 4-18-4-18-4 Ug 0,5 | 100 | 3.0 | Dřevěný rám 92 mm | Dřevěný lepený eurohranol | Bílý lak | Dřevěný lepený eurohranol | Okenní klika | není | Celoobvodové kování s pětibodovým uzávěrem | Dvojkřídlové okno otevíravé a sklápěcí, symetricky dělené s nadsvětlíkem | 1452Obj0798437606 | Kus | Okno - objekt+SmartPart | 2.0584 | 80 | 80 | 80 | 0.8 | no | 2.1 | 1.5 | 3.15
O06 | Půdorys 1.NP | 2.1 | 1.5 | WINDOW | 0 | 0 | 2.2 | O06 | MainObject | SmartPartCompressed | Izolační trojsklo 4-18-4-18-4 Ug 0,5 | 100 | 3.0 | Dřevěný rám 92 mm | Dřevěný lepený eurohranol | Bílý lak | Dřevěný lepený eurohranol | Okenní klika | není | Celoobvodové kování s pětibodovým uzávěrem | Dvojkřídlové okno otevíravé a sklápěcí, symetricky dělené s nadsvětlíkem | 1452Obj0798437615 | Kus | Okno - objekt+SmartPart | 2.0584 | 80 | 80 | 80 | 0.8 | no | 2.1 | 1.5 | 3.15
O06 | Půdorys 1.NP | 2.1 | 1.5 | WINDOW | 0 | 0 | 2.2 | O06 | MainObject | SmartPartCompressed | Izolační trojsklo 4-18-4-18-4 Ug 0,5 | 100 | 3.0 | Dřevěný rám 92 mm | Dřevěný lepený eurohranol | Bílý lak | Dřevěný lepený eurohranol | Okenní klika | není | Celoobvodové kování s pětibodovým uzávěrem | Dvojkřídlové okno otevíravé a sklápěcí, symetricky dělené s nadsvětlíkem | 1452Obj0798437624 | Kus | Okno - objekt+SmartPart | 2.0584 | 80 | 80 | 80 | 0.8 | no | 2.1 | 1.5 | 3.15
O06 | Půdorys 1.NP | 2.1 | 1.5 | WINDOW | 0 | 0 | 2.2 | O06 | MainObject | SmartPartCompressed | Izolační trojsklo 4-18-4-18-4 Ug 0,5 | 100 | 3.0 | Dřevěný rám 92 mm | Dřevěný lepený eurohranol | Bílý lak | Dřevěný lepený eurohranol | Okenní klika | není | Celoobvodové kování s pětibodovým uzávěrem | Dvojkřídlové okno otevíravé a sklápěcí, symetricky dělené s nadsvětlíkem | 1452Obj0798437633 | Kus | Okno - objekt+SmartPart | 2.0584 | 80 | 80 | 80 | 0.8 | no | 2.1 | 1.5 | 3.15
O06 | Půdorys 1.NP | 2.1 | 1.5 | WINDOW | 0 | 0 | 2.2 | O06 | MainObject | SmartPartCompressed | Izolační trojsklo 4-18-4-18-4 Ug 0,5 | 100 | 3.0 | Dřevěný rám 92 mm | Dřevěný lepený eurohranol | Bílý lak | Dřevěný lepený eurohranol | Okenní klika | není | Celoobvodové kování s pětibodovým uzávěrem | Dvojkřídlové okno otevíravé a sklápěcí, symetricky dělené s nadsvětlíkem | 1452Obj0798437642 | Kus | Okno - objekt+SmartPart | 2.0584 | 80 | 80 | 80 | 0.8 | no | 2.1 | 1.5 | 3.15
O06 | Půdorys 1.NP | 2.1 | 1.5 | WINDOW | 0 | 0 | 2.2 | O06 | MainObject | SmartPartCompressed | Izolační trojsklo 4-18-4-18-4 Ug 0,5 | 100 | 3.0 | Dřevěný rám 92 mm | Dřevěný lepený eurohranol | Bílý lak | Dřevěný lepený eurohranol | Okenní klika | není | Celoobvodové kování s pětibodovým uzávěrem | Dvojkřídlové okno otevíravé a sklápěcí, symetricky dělené s nadsvětlíkem | 1452Obj0798437651 | Kus | Okno - objekt+SmartPart | 2.0584 | 80 | 80 | 80 | 0.8 | no | 2.1 | 1.5 | 3.15
O06 | Půdorys 1.NP | 2.1 | 1.5 | WINDOW | 0 | 0 | 2.2 | O06 | MainObject | SmartPartCompressed | Izolační trojsklo 4-18-4-18-4 Ug 0,5 | 100 | 3.0 | Dřevěný rám 92 mm | Dřevěný lepený eurohranol | Bílý lak | Dřevěný lepený eurohranol | Okenní klika | není | Celoobvodové kování s pětibodovým uzávěrem | Dvojkřídlové okno otevíravé a sklápěcí, symetricky dělené s nadsvětlíkem | 1452Obj0798437660 | Kus | Okno - objekt+SmartPart | 2.0584 | 80 | 80 | 80 | 0.8 | no | 2.1 | 1.5 | 3.15
O06 | Půdorys 1.NP | 2.1 | 1.5 | WINDOW | 0 | 0 | 2.2 | O06 | MainObject | SmartPartCompressed | Izolační trojsklo 4-18-4-18-4 Ug 0,5 | 100 | 3.0 | Dřevěný rám 92 mm | Dřevěný lepený eurohranol | Bílý lak | Dřevěný lepený eurohranol | Okenní klika | není | Celoobvodové kování s pětibodovým uzávěrem | Dvojkřídlové okno otevíravé a sklápěcí, symetricky dělené s nadsvětlíkem | 1452Obj0798437511 | Kus | Okno - objekt+SmartPart | 2.0584 | 80 | 80 | 80 | 0.8 | no | 2.1 | 1.5 | 3.15
O06 | Půdorys 1.NP | 2.1 | 1.5 | WINDOW | 0 | 0 | 2.2 | O06 | MainObject | SmartPartCompressed | Izolační trojsklo 4-18-4-18-4 Ug 0,5 | 100 | 3.0 | Dřevěný rám 92 mm | Dřevěný lepený eurohranol | Bílý lak | Dřevěný lepený eurohranol | Okenní klika | není | Celoobvodové kování s pětibodovým uzávěrem | Dvojkřídlové okno otevíravé a sklápěcí, symetricky dělené s nadsvětlíkem | 1452Obj0798437719 | Kus | Okno - objekt+SmartPart | 2.0584 | 80 | 80 | 80 | 0.8 | no | 2.1 | 1.5 | 3.15
O06 | Půdorys 1.NP | 2.1 | 1.5 | WINDOW | 0 | 0 | 2.2 | O06 | MainObject | SmartPartCompressed | Izolační trojsklo 4-18-4-18-4 Ug 0,5 | 100 | 3.0 | Dřevěný rám 92 mm | Dřevěný lepený eurohranol | Bílý lak | Dřevěný lepený eurohranol | Okenní klika | není | Celoobvodové kování s pětibodovým uzávěrem | Dvojkřídlové okno otevíravé a sklápěcí, symetricky dělené s nadsvětlíkem | 1452Obj0798437398 | Kus | Okno - objekt+SmartPart | 2.0584 | 80 | 80 | 80 | 0.8 | no | 2.1 | 1.5 | 3.15
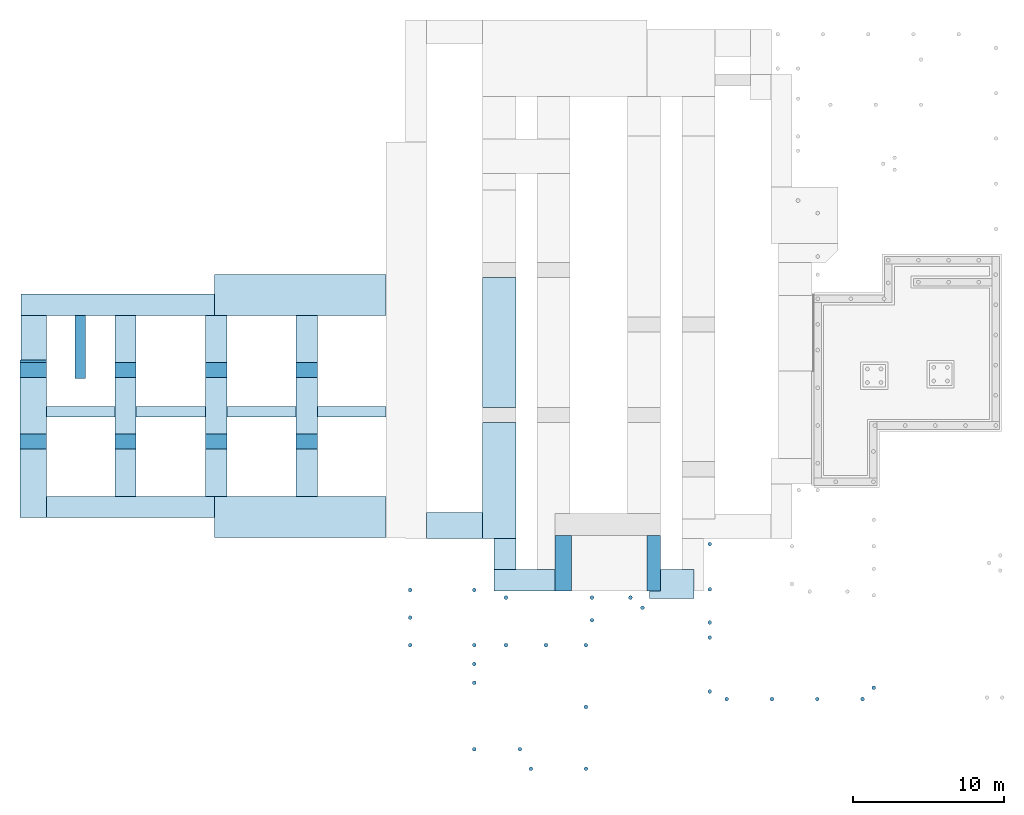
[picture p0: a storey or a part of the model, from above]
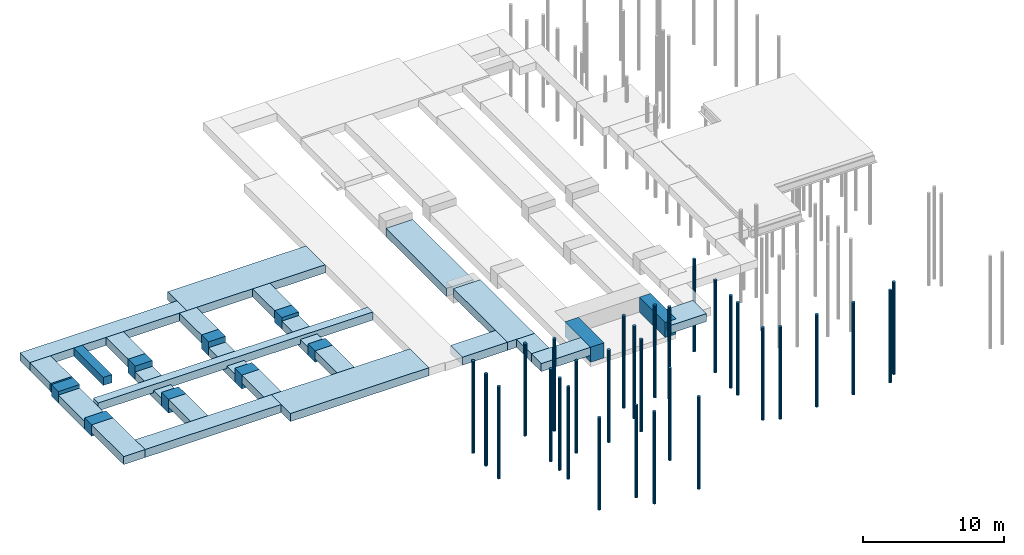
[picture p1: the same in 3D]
Properties of the parts of a building model (IFC4), part 44 of 45

# IfcWindow (265)
Name | In | OverallHeight (m) | OverallWidth (m) | PredefinedType | Dolní_hrana (m) = Horní_hrana (m) | Jednotková_cena = HeightWindowSillOutside = HeightWindowSillInside = OffsetOpeningBottom = OffsetOpeningTop = OffsetOpeningLeft = OffsetOpeningRight = Perimeter (m) | Verze programu | Označení | Plugin_Bezeichnung | Plugin_Objektname | Typ skla | Uvažované procento prosklení | Verze | Zárubeň/Rám_Typ | Zárubeň/Rám_Materiál | Zárubeň/Rám_Povrch = Křídlo_Povrch_Int. = Křídlo_Povrch_Ext. | Křídlo_Materiál | Kování_Klika_Int. | Kování_Klika_Ext. = Kování_Zámek | Kování_Závěsy | Specifikace | Allright_Stavebni_dil_ID | Jednotka | Název_objektu | GlassSurface | DeductionOpeningBottom | DeductionOpeningLeft = DeductionOpeningRight | DeductionOpeningTop | ThermalTransmittance (W/K/m2) | SmokeStop = FireExit | Height (m) | Width (m) | Area (m2)
O06 | Půdorys 1.NP | 2.1 | 1.5 | WINDOW | 0 | 0 | 2.2 | O06 | MainObject | SmartPartCompressed | Izolační trojsklo 4-18-4-18-4 Ug 0,5 | 100 | 3.0 | Dřevěný rám 92 mm | Dřevěný lepený eurohranol | Bílý lak | Dřevěný lepený eurohranol | Okenní klika | není | Celoobvodové kování s pětibodovým uzávěrem | Dvojkřídlové okno otevíravé a sklápěcí, symetricky dělené s nadsvětlíkem | 1452Obj0798437407 | Kus | Okno - objekt+SmartPart | 2.0584 | 80 | 80 | 80 | 0.8 | no | 2.1 | 1.5 | 3.15
O06 | Půdorys 1.NP | 2.1 | 1.5 | WINDOW | 0 | 0 | 2.2 | O06 | MainObject | SmartPartCompressed | Izolační trojsklo 4-18-4-18-4 Ug 0,5 | 100 | 3.0 | Dřevěný rám 92 mm | Dřevěný lepený eurohranol | Bílý lak | Dřevěný lepený eurohranol | Okenní klika | není | Celoobvodové kování s pětibodovým uzávěrem | Dvojkřídlové okno otevíravé a sklápěcí, symetricky dělené s nadsvětlíkem | 1452Obj0798437416 | Kus | Okno - objekt+SmartPart | 2.0584 | 80 | 80 | 80 | 0.8 | no | 2.1 | 1.5 | 3.15
O06 | Půdorys 1.NP | 2.1 | 1.5 | WINDOW | 0 | 0 | 2.2 | O06 | MainObject | SmartPartCompressed | Izolační trojsklo 4-18-4-18-4 Ug 0,5 | 100 | 3.0 | Dřevěný rám 92 mm | Dřevěný lepený eurohranol | Bílý lak | Dřevěný lepený eurohranol | Okenní klika | není | Celoobvodové kování s pětibodovým uzávěrem | Dvojkřídlové okno otevíravé a sklápěcí, symetricky dělené s nadsvětlíkem | 1452Obj0798437425 | Kus | Okno - objekt+SmartPart | 2.0584 | 80 | 80 | 80 | 0.8 | no | 2.1 | 1.5 | 3.15
O06 | Půdorys 1.NP | 2.1 | 1.5 | WINDOW | 0 | 0 | 2.2 | O06 | MainObject | SmartPartCompressed | Izolační trojsklo 4-18-4-18-4 Ug 0,5 | 100 | 3.0 | Dřevěný rám 92 mm | Dřevěný lepený eurohranol | Bílý lak | Dřevěný lepený eurohranol | Okenní klika | není | Celoobvodové kování s pětibodovým uzávěrem | Dvojkřídlové okno otevíravé a sklápěcí, symetricky dělené s nadsvětlíkem | 1452Obj0798437443 | Kus | Okno - objekt+SmartPart | 2.0584 | 80 | 80 | 80 | 0.8 | no | 2.1 | 1.5 | 3.15
O06 | Půdorys 1.NP | 2.1 | 1.5 | WINDOW | 0 | 0 | 2.2 | O06 | MainObject | SmartPartCompressed | Izolační trojsklo 4-18-4-18-4 Ug 0,5 | 100 | 3.0 | Dřevěný rám 92 mm | Dřevěný lepený eurohranol | Bílý lak | Dřevěný lepený eurohranol | Okenní klika | není | Celoobvodové kování s pětibodovým uzávěrem | Dvojkřídlové okno otevíravé a sklápěcí, symetricky dělené s nadsvětlíkem | 1452Obj0798437452 | Kus | Okno - objekt+SmartPart | 2.0584 | 80 | 80 | 80 | 0.8 | no | 2.1 | 1.5 | 3.15
O06 | Půdorys 1.NP | 2.1 | 1.5 | WINDOW | 0 | 0 | 2.2 | O06 | MainObject | SmartPartCompressed | Izolační trojsklo 4-18-4-18-4 Ug 0,5 | 100 | 3.0 | Dřevěný rám 92 mm | Dřevěný lepený eurohranol | Bílý lak | Dřevěný lepený eurohranol | Okenní klika | není | Celoobvodové kování s pětibodovým uzávěrem | Dvojkřídlové okno otevíravé a sklápěcí, symetricky dělené s nadsvětlíkem | 1452Obj0798437303 | Kus | Okno - objekt+SmartPart | 2.0584 | 80 | 80 | 80 | 0.8 | no | 2.1 | 1.5 | 3.15
O06 | Půdorys 1.NP | 2.1 | 1.5 | WINDOW | 0 | 0 | 2.2 | O06 | MainObject | SmartPartCompressed | Izolační trojsklo 4-18-4-18-4 Ug 0,5 | 100 | 3.0 | Dřevěný rám 92 mm | Dřevěný lepený eurohranol | Bílý lak | Dřevěný lepený eurohranol | Okenní klika | není | Celoobvodové kování s pětibodovým uzávěrem | Dvojkřídlové okno otevíravé a sklápěcí, symetricky dělené s nadsvětlíkem | 1452Obj0798437434 | Kus | Okno - objekt+SmartPart | 2.0584 | 80 | 80 | 80 | 0.8 | no | 2.1 | 1.5 | 3.15
O06 | Půdorys 1.NP | 1.95 | 1.5 | WINDOW | 0 | 0 | 2.2 | O06 | MainObject | SmartPartCompressed | Izolační trojsklo 4-18-4-18-4 Ug 0,5 | 100 | 3.0 | Dřevěný rám 92 mm | Dřevěný lepený eurohranol | Bílý lak | Dřevěný lepený eurohranol | Okenní klika | není | Celoobvodové kování s pětibodovým uzávěrem | Dvojkřídlové okno otevíravé a sklápěcí, symetricky dělené s nadsvětlíkem | 1452Obj0798436752 | Kus | Okno - objekt+SmartPart | 1.8724 | 80 | 80 | 80 | 0.8 | no | 1.95 | 1.5 | 2.925
O06 | Půdorys 1.NP | 1.95 | 1.5 | WINDOW | 0 | 0 | 2.2 | O06 | MainObject | SmartPartCompressed | Izolační trojsklo 4-18-4-18-4 Ug 0,5 | 100 | 3.0 | Dřevěný rám 92 mm | Dřevěný lepený eurohranol | Bílý lak | Dřevěný lepený eurohranol | Okenní klika | není | Celoobvodové kování s pětibodovým uzávěrem | Dvojkřídlové okno otevíravé a sklápěcí, symetricky dělené s nadsvětlíkem | 1452Obj0798436796 | Kus | Okno - objekt+SmartPart | 1.8724 | 80 | 80 | 80 | 0.8 | no | 1.95 | 1.5 | 2.925
O06 | Půdorys 1.NP | 1.95 | 1.5 | WINDOW | 0 | 0 | 2.2 | O06 | MainObject | SmartPartCompressed | Izolační trojsklo 4-18-4-18-4 Ug 0,5 | 100 | 3.0 | Dřevěný rám 92 mm | Dřevěný lepený eurohranol | Bílý lak | Dřevěný lepený eurohranol | Okenní klika | není | Celoobvodové kování s pětibodovým uzávěrem | Dvojkřídlové okno otevíravé a sklápěcí, symetricky dělené s nadsvětlíkem | 1452Obj0798436804 | Kus | Okno - objekt+SmartPart | 1.8724 | 80 | 80 | 80 | 0.8 | no | 1.95 | 1.5 | 2.925
O06 | Půdorys 1.NP | 1.8 | 1.2 | WINDOW | 0 | 0 | 2.2 | O06 | MainObject | SmartPartCompressed | Izolační trojsklo 4-18-4-18-4 Ug 0,5 | 100 | 3.0 | Dřevěný rám 92 mm | Dřevěný lepený eurohranol | Bílý lak | Dřevěný lepený eurohranol | Okenní klika | není | Celoobvodové kování s pětibodovým uzávěrem | Dvojkřídlové okno otevíravé a sklápěcí, symetricky dělené s nadsvětlíkem | 1452Obj0798439157 | Kus | Okno - objekt+SmartPart | 1.4476 | 80 | 80 | 80 | 0.8 | no | 1.8 | 1.2 | 2.16
O06 | Půdorys 1.NP | 1.8 | 1.2 | WINDOW | 0 | 0 | 2.2 | O06 | MainObject | SmartPartCompressed | Izolační trojsklo 4-18-4-18-4 Ug 0,5 | 100 | 3.0 | Dřevěný rám 92 mm | Dřevěný lepený eurohranol | Bílý lak | Dřevěný lepený eurohranol | Okenní klika | není | Celoobvodové kování s pětibodovým uzávěrem | Dvojkřídlové okno otevíravé a sklápěcí, symetricky dělené s nadsvětlíkem | 1452Obj0798439166 | Kus | Okno - objekt+SmartPart | 1.4476 | 80 | 80 | 80 | 0.8 | no | 1.8 | 1.2 | 2.16
O06 | Půdorys 1.NP | 1.8 | 1.2 | WINDOW | 0 | 0 | 2.2 | O06 | MainObject | SmartPartCompressed | Izolační trojsklo 4-18-4-18-4 Ug 0,5 | 100 | 3.0 | Dřevěný rám 92 mm | Dřevěný lepený eurohranol | Bílý lak | Dřevěný lepený eurohranol | Okenní klika | není | Celoobvodové kování s pětibodovým uzávěrem | Dvojkřídlové okno otevíravé a sklápěcí, symetricky dělené s nadsvětlíkem | 1452Obj0798436904 | Kus | Okno - objekt+SmartPart | 1.4476 | 80 | 80 | 80 | 0.8 | no | 1.8 | 1.2 | 2.16
O06 | Půdorys 1.NP | 1.95 | 1.05 | WINDOW | 0 | 0 | 2.2 | O06 | MainObject | SmartPartCompressed | Izolační trojsklo 4-18-4-18-4 Ug 0,5 | 100 | 3.0 | Dřevěný rám 92 mm | Dřevěný lepený eurohranol | Bílý lak | Dřevěný lepený eurohranol | Okenní klika | není | Celoobvodové kování s pětibodovým uzávěrem | Dvojkřídlové okno otevíravé a sklápěcí, symetricky dělené s nadsvětlíkem | 1452Obj0798436708 | Kus | Okno - objekt+SmartPart | 1.1929 | 80 | 80 | 80 | 0.8 | no | 1.95 | 1.05 | 2.047
O01 | Půdorys 1.NP | 1 | 0.5 | WINDOW | 0 | 0 | 2.2 | O01 | MainObject | SmartPartCompressed |  | 100 | 3.0 | Dřevěný rám 92 mm | Dřevěný lepený eurohranol | Bílý lak | Dřevěný lepený eurohranol | Okenní klika | není | Celoobvodové kování s pětibodovým uzávěrem |  | 1452Obj0798446610 | Kus | Okno - objekt+SmartPart | 0 | 20 | 20 | 20 | 0.8 | no | 1 | 0.5 | 0.5
O01 | Půdorys 1.NP | 1.2 | 0.6 | WINDOW | 0 | 0 | 2.2 | O01 | MainObject | SmartPartCompressed |  | 100 | 3.0 | Dřevěný rám 92 mm | Dřevěný lepený eurohranol | Bílý lak | Dřevěný lepený eurohranol | Okenní klika | není | Celoobvodové kování s pětibodovým uzávěrem |  | 1452Obj0798447115 | Kus | Okno - objekt+SmartPart | 0 | 20 | 20 | 20 | 0.8 | no | 1.2 | 0.6 | 0.72
O01 | Půdorys 1.NP | 1.2 | 0.45 | WINDOW | 0 | 0 | 2.2 | O01 | MainObject | SmartPartCompressed |  | 100 | 3.0 | Dřevěný rám 92 mm | Dřevěný lepený eurohranol | Bílý lak | Dřevěný lepený eurohranol | Okenní klika | není | Celoobvodové kování s pětibodovým uzávěrem |  | 1452Obj0798447001 | Kus | Okno - objekt+SmartPart | 0 | 20 | 20 | 20 | 0.8 | no | 1.2 | 0.45 | 0.54
O01 | Půdorys 1.NP | 1.2 | 0.45 | WINDOW | 0 | 0 | 2.2 | O01 | MainObject | SmartPartCompressed |  | 100 | 3.0 | Dřevěný rám 92 mm | Dřevěný lepený eurohranol | Bílý lak | Dřevěný lepený eurohranol | Okenní klika | není | Celoobvodové kování s pětibodovým uzávěrem |  | 1452Obj0798447078 | Kus | Okno - objekt+SmartPart | 0 | 20 | 20 | 20 | 0.8 | no | 1.2 | 0.45 | 0.54
O01 | Půdorys 1.NP | 1 | 0.5 | WINDOW | 0 | 0 | 2.2 | O01 | MainObject | SmartPartCompressed |  | 100 | 3.0 | Dřevěný rám 92 mm | Dřevěný lepený eurohranol | Bílý lak | Dřevěný lepený eurohranol | Okenní klika | není | Celoobvodové kování s pětibodovým uzávěrem |  | 1452Obj0798447149 | Kus | Okno - objekt+SmartPart | 0 | 20 | 20 | 20 | 0.8 | no | 1 | 0.5 | 0.5
O01 | Půdorys 1.NP | 1 | 0.5 | WINDOW | 0 | 0 | 2.2 | O01 | MainObject | SmartPartCompressed |  | 100 | 3.0 | Dřevěný rám 92 mm | Dřevěný lepený eurohranol | Bílý lak | Dřevěný lepený eurohranol | Okenní klika | není | Celoobvodové kování s pětibodovým uzávěrem |  | 1452Obj1096101695 | Kus | Okno - objekt+SmartPart | 0 | 20 | 20 | 20 | 0.8 | no | 1 | 0.5 | 0.5
O01 | Půdorys 1.NP | 1 | 0.5 | WINDOW | 0 | 0 | 2.2 | O01 | MainObject | SmartPartCompressed |  | 100 | 3.0 | Dřevěný rám 92 mm | Dřevěný lepený eurohranol | Bílý lak | Dřevěný lepený eurohranol | Okenní klika | není | Celoobvodové kování s pětibodovým uzávěrem |  | 1452Obj1096102981 | Kus | Okno - objekt+SmartPart | 0 | 20 | 20 | 20 | 0.8 | no | 1 | 0.5 | 0.5
O01 | Půdorys 1.NP | 1 | 0.4 | WINDOW | 0 | 0 | 2.2 | O01 | MainObject | SmartPartCompressed |  | 100 | 3.0 | Dřevěný rám 92 mm | Dřevěný lepený eurohranol | Bílý lak | Dřevěný lepený eurohranol | Okenní klika | není | Celoobvodové kování s pětibodovým uzávěrem |  | 1452Obj1096104480 | Kus | Okno - objekt+SmartPart | 0 | 20 | 20 | 20 | 0.8 | no | 1 | 0.4 | 0.4
O01 | Půdorys 1.NP | 0.4 | 0.4 | WINDOW | 0 | 0 | 2.2 | O01 | MainObject | SmartPartCompressed |  | 100 | 3.0 | Dřevěný rám 92 mm | Dřevěný lepený eurohranol | Bílý lak | Dřevěný lepený eurohranol | Okenní klika | není | Celoobvodové kování s pětibodovým uzávěrem |  | 1452Obj1096112229 | Kus | Okno - objekt+SmartPart | 0 | 20 | 20 | 20 | 0.8 | no | 0.4 | 0.4 | 0.16
O01 | Půdorys 1.NP | 1 | 0.5 | WINDOW | 0 | 0 | 2.2 | O01 | MainObject | SmartPartCompressed |  | 100 | 3.0 | Dřevěný rám 92 mm | Dřevěný lepený eurohranol | Bílý lak | Dřevěný lepený eurohranol | Okenní klika | není | Celoobvodové kování s pětibodovým uzávěrem |  | 1452Obj1096116847 | Kus | Okno - objekt+SmartPart | 0 | 20 | 20 | 20 | 0.8 | no | 1 | 0.5 | 0.5
O01 | Půdorys 1.NP | 1 | 0.5 | WINDOW | 0 | 0 | 2.2 | O01 | MainObject | SmartPartCompressed |  | 100 | 3.0 | Dřevěný rám 92 mm | Dřevěný lepený eurohranol | Bílý lak | Dřevěný lepený eurohranol | Okenní klika | není | Celoobvodové kování s pětibodovým uzávěrem |  | 1452Obj1096116658 | Kus | Okno - objekt+SmartPart | 0 | 20 | 20 | 20 | 0.8 | no | 1 | 0.5 | 0.5
O01 | Půdorys 1.NP | 1 | 0.5 | WINDOW | 0 | 0 | 2.2 | O01 | MainObject | SmartPartCompressed |  | 100 | 3.0 | Dřevěný rám 92 mm | Dřevěný lepený eurohranol | Bílý lak | Dřevěný lepený eurohranol | Okenní klika | není | Celoobvodové kování s pětibodovým uzávěrem |  | 1452Obj1096116958 | Kus | Okno - objekt+SmartPart | 0 | 20 | 20 | 20 | 0.8 | no | 1 | 0.5 | 0.5
O06 | Půdorys 1.NP | 1.1 | 2.5 | WINDOW | 0 | 0 | 2.2 | O06 | MainObject | SmartPartCompressed | Izolační trojsklo 4-18-4-18-4 Ug 0,5 | 100 | 3.0 | Dřevěný rám 92 mm | Dřevěný lepený eurohranol | Bílý lak | Dřevěný lepený eurohranol | Okenní klika | není | Celoobvodové kování s pětibodovým uzávěrem | Dvojkřídlové okno otevíravé a sklápěcí, symetricky dělené s nadsvětlíkem | 1452Obj1096117645 | Kus | Okno - objekt+SmartPart | 1.8816 | 80 | 80 | 80 | 0.8 | no | 1.1 | 2.5 | 2.75
O01 | Půdorys 1.NP | 1.2 | 0.6 | WINDOW | 0 | 0 | 2.2 | O01 | MainObject | SmartPartCompressed |  | 100 | 3.0 | Dřevěný rám 92 mm | Dřevěný lepený eurohranol | Bílý lak | Dřevěný lepený eurohranol | Okenní klika | není | Celoobvodové kování s pětibodovým uzávěrem |  | 1452Obj1096220507 | Kus | Okno - objekt+SmartPart | 0 | 20 | 20 | 20 | 0.8 | no | 1.2 | 0.6 | 0.72
O06 | Půdorys 1.NP | 1.5 | 1.5 | WINDOW | 0 | 0 | 2.2 | O06 | MainObject | SmartPartCompressed | Izolační trojsklo 4-18-4-18-4 Ug 0,5 | 100 | 3.0 | Dřevěný rám 92 mm | Dřevěný lepený eurohranol | Bílý lak | Dřevěný lepený eurohranol | Okenní klika | není | Celoobvodové kování s pětibodovým uzávěrem | Dvojkřídlové okno otevíravé a sklápěcí, symetricky dělené s nadsvětlíkem | 1452Obj0798438973 | Kus | Okno - objekt+SmartPart | 1.5376 | 80 | 80 | 80 | 0.8 | no | 1.5 | 1.5 | 2.25
O06 | Půdorys 1.NP | 1.5 | 1.5 | WINDOW | 0 | 0 | 2.2 | O06 | MainObject | SmartPartCompressed | Izolační trojsklo 4-18-4-18-4 Ug 0,5 | 100 | 3.0 | Dřevěný rám 92 mm | Dřevěný lepený eurohranol | Bílý lak | Dřevěný lepený eurohranol | Okenní klika | není | Celoobvodové kování s pětibodovým uzávěrem | Dvojkřídlové okno otevíravé a sklápěcí, symetricky dělené s nadsvětlíkem | 1452Obj0798438982 | Kus | Okno - objekt+SmartPart | 1.5376 | 80 | 80 | 80 | 0.8 | no | 1.5 | 1.5 | 2.25
O06 | Půdorys 1.NP | 1.5 | 1.5 | WINDOW | 0 | 0 | 2.2 | O06 | MainObject | SmartPartCompressed | Izolační trojsklo 4-18-4-18-4 Ug 0,5 | 100 | 3.0 | Dřevěný rám 92 mm | Dřevěný lepený eurohranol | Bílý lak | Dřevěný lepený eurohranol | Okenní klika | není | Celoobvodové kování s pětibodovým uzávěrem | Dvojkřídlové okno otevíravé a sklápěcí, symetricky dělené s nadsvětlíkem | 1452Obj0798438912 | Kus | Okno - objekt+SmartPart | 1.5376 | 80 | 80 | 80 | 0.8 | no | 1.5 | 1.5 | 2.25
O01 | Půdorys 1.NP | 0.3 | 0.3 | WINDOW | 0 | 0 | 2.2 | O01 | MainObject | SmartPartCompressed |  | 100 | 3.0 | Dřevěný rám 92 mm | Dřevěný lepený eurohranol | Bílý lak | Dřevěný lepený eurohranol | Okenní klika | není | Celoobvodové kování s pětibodovým uzávěrem |  | 1452Obj1096116075 | Kus | Okno - objekt+SmartPart | 0 | 20 | 20 | 20 | 0.8 | no | 0.3 | 0.3 | 0.09
II.OH01 | Půdorys 1.NP | 0.75 | 1.5 | WINDOW |  | 0 | 2.2 | II.OH01 | MainObject | SmartPartCompressed | Izolační trojsklo 4-18-4-18-4 | 100 | 3.0 | Hliníkový profil 95 mm | Hliníkový profil | Lak bílý hliník - RAL 9006 | Hliníkový profil | Pákový ovladač | není | Celoobvodové kování | Jednokřídlové okno sklápěcí | 1464Obj1096167527 | Kus | Okno - objekt+SmartPart | 0.6076 | 80 | 80 | 80 | 0.8 | no | 0.75 | 1.5 | 1.125 | Pset_WindowCommon - Status: NEW; SecurityRating: bez; NEMSOK - Kód prvku: ON03.03.2001; Podlaží: 1.NP; Součinitel prostupu tepla - zasklení (Ug): Ug 0,6; Typ otevírání: Jednokřídlové okno sklápěcí; Solární faktor: 0.52; Světelný činitel prostupu: 0.74; Průvzdušnost: 4; Zasklení: Izolační trojsklo 4-18-4-18-4; Připojení EZS: Ano; Připojení NN: Ne; Připojení EPS: Ne; Připojení MaR: Ne; Vnitřní parapet - materiál: Keramický obklad; Horní podlaží: 1.NP
I.OH01 | Půdorys 1.NP | 0.75 | 1.5 | WINDOW |  | 0 | 2.2 | I.OH01 | MainObject | SmartPartCompressed | Izolační trojsklo 4-18-4-18-4 | 100 | 3.0 | Hliníkový profil 95 mm | Hliníkový profil | Lak bílý hliník - RAL 9006 | Hliníkový profil | Pákový ovladač | není | Celoobvodové kování | Jednokřídlové okno sklápěcí | 1464Obj1096168449 | Kus | Okno - objekt+SmartPart | 0.6076 | 80 | 80 | 80 | 0.8 | no | 0.75 | 1.5 | 1.125 | Pset_WindowCommon - Status: NEW; SecurityRating: bez; NEMSOK - Kód prvku: ON03.03.1001; Podlaží: 1.NP; Součinitel prostupu tepla - zasklení (Ug): Ug 0,6; Typ otevírání: Jednokřídlové okno sklápěcí; Solární faktor: 0.52; Světelný činitel prostupu: 0.74; Průvzdušnost: 4; Zasklení: Izolační trojsklo 4-18-4-18-4; Připojení EZS: Ano; Připojení NN: Ne; Připojení EPS: Ne; Připojení MaR: Ne; Vnitřní parapet - materiál: Vlhkuodolná DTD; Horní podlaží: 1.NP
I.OH01 | Půdorys 1.NP | 0.75 | 1.5 | WINDOW |  | 0 | 2.2 | I.OH01 | MainObject | SmartPartCompressed | Izolační trojsklo 4-18-4-18-4 | 100 | 3.0 | Hliníkový profil 95 mm | Hliníkový profil | Lak bílý hliník - RAL 9006 | Hliníkový profil | Pákový ovladač | není | Celoobvodové kování | Jednokřídlové okno sklápěcí | 1464Obj1096168506 | Kus | Okno - objekt+SmartPart | 0.6076 | 80 | 80 | 80 | 0.8 | no | 0.75 | 1.5 | 1.125 | Pset_WindowCommon - Status: NEW; SecurityRating: bez; NEMSOK - Kód prvku: ON03.03.1001; Podlaží: 1.NP; Součinitel prostupu tepla - zasklení (Ug): Ug 0,6; Typ otevírání: Jednokřídlové okno sklápěcí; Solární faktor: 0.52; Světelný činitel prostupu: 0.74; Průvzdušnost: 4; Zasklení: Izolační trojsklo 4-18-4-18-4; Připojení EZS: Ano; Připojení NN: Ne; Připojení EPS: Ne; Připojení MaR: Ne; Vnitřní parapet - materiál: Vlhkuodolná DTD; Horní podlaží: 1.NP
I.OH01 | Půdorys 1.NP | 0.75 | 1.5 | WINDOW |  | 0 | 2.2 | I.OH01 | MainObject | SmartPartCompressed | Izolační trojsklo 4-18-4-18-4 | 100 | 3.0 | Hliníkový profil 95 mm | Hliníkový profil | Lak bílý hliník - RAL 9006 | Hliníkový profil | Pákový ovladač | není | Celoobvodové kování | Jednokřídlové okno sklápěcí | 1464Obj1096168548 | Kus | Okno - objekt+SmartPart | 0.6076 | 80 | 80 | 80 | 0.8 | no | 0.75 | 1.5 | 1.125 | Pset_WindowCommon - Status: NEW; SecurityRating: bez; NEMSOK - Kód prvku: ON03.03.1001; Podlaží: 1.NP; Součinitel prostupu tepla - zasklení (Ug): Ug 0,6; Typ otevírání: Jednokřídlové okno sklápěcí; Solární faktor: 0.52; Světelný činitel prostupu: 0.74; Průvzdušnost: 4; Zasklení: Izolační trojsklo 4-18-4-18-4; Připojení EZS: Ano; Připojení NN: Ne; Připojení EPS: Ne; Připojení MaR: Ne; Vnitřní parapet - materiál: Vlhkuodolná DTD; Horní podlaží: 1.NP
I.OH01 | Půdorys 1.NP | 0.75 | 1.5 | WINDOW |  | 0 | 2.2 | I.OH01 | MainObject | SmartPartCompressed | Izolační trojsklo 4-18-4-18-4 | 100 | 3.0 | Hliníkový profil 95 mm | Hliníkový profil | Lak bílý hliník - RAL 9006 | Hliníkový profil | Pákový ovladač | není | Celoobvodové kování | Jednokřídlové okno sklápěcí | 1464Obj1096168610 | Kus | Okno - objekt+SmartPart | 0.6076 | 80 | 80 | 80 | 0.8 | no | 0.75 | 1.5 | 1.125 | Pset_WindowCommon - Status: NEW; SecurityRating: bez; NEMSOK - Kód prvku: ON03.03.1001; Podlaží: 1.NP; Součinitel prostupu tepla - zasklení (Ug): Ug 0,6; Typ otevírání: Jednokřídlové okno sklápěcí; Solární faktor: 0.52; Světelný činitel prostupu: 0.74; Průvzdušnost: 4; Zasklení: Izolační trojsklo 4-18-4-18-4; Připojení EZS: Ano; Připojení NN: Ne; Připojení EPS: Ne; Připojení MaR: Ne; Vnitřní parapet - materiál: Vlhkuodolná DTD; Horní podlaží: 1.NP
I.OH01 | Půdorys 1.NP | 0.75 | 1.5 | WINDOW |  | 0 | 2.2 | I.OH01 | MainObject | SmartPartCompressed | Izolační trojsklo 4-18-4-18-4 | 100 | 3.0 | Hliníkový profil 95 mm | Hliníkový profil | Lak bílý hliník - RAL 9006 | Hliníkový profil | Pákový ovladač | není | Celoobvodové kování | Jednokřídlové okno sklápěcí | 1464Obj1096168645 | Kus | Okno - objekt+SmartPart | 0.6076 | 80 | 80 | 80 | 0.8 | no | 0.75 | 1.5 | 1.125 | Pset_WindowCommon - Status: NEW; SecurityRating: bez; NEMSOK - Kód prvku: ON03.03.1001; Podlaží: 1.NP; Součinitel prostupu tepla - zasklení (Ug): Ug 0,6; Typ otevírání: Jednokřídlové okno sklápěcí; Solární faktor: 0.52; Světelný činitel prostupu: 0.74; Průvzdušnost: 4; Zasklení: Izolační trojsklo 4-18-4-18-4; Připojení EZS: Ano; Připojení NN: Ne; Připojení EPS: Ne; Připojení MaR: Ne; Vnitřní parapet - materiál: Vlhkuodolná DTD; Horní podlaží: 1.NP
I.OH01 | Půdorys 1.NP | 0.75 | 1.5 | WINDOW |  | 0 | 2.2 | I.OH01 | MainObject | SmartPartCompressed | Izolační trojsklo 4-18-4-18-4 | 100 | 3.0 | Hliníkový profil 95 mm | Hliníkový profil | Lak bílý hliník - RAL 9006 | Hliníkový profil | Pákový ovladač | není | Celoobvodové kování | Jednokřídlové okno sklápěcí | 1464Obj1096168676 | Kus | Okno - objekt+SmartPart | 0.6076 | 80 | 80 | 80 | 0.8 | no | 0.75 | 1.5 | 1.125 | Pset_WindowCommon - Status: NEW; SecurityRating: bez; NEMSOK - Kód prvku: ON03.03.1001; Podlaží: 1.NP; Součinitel prostupu tepla - zasklení (Ug): Ug 0,6; Typ otevírání: Jednokřídlové okno sklápěcí; Solární faktor: 0.52; Světelný činitel prostupu: 0.74; Průvzdušnost: 4; Zasklení: Izolační trojsklo 4-18-4-18-4; Připojení EZS: Ano; Připojení NN: Ne; Připojení EPS: Ne; Připojení MaR: Ne; Vnitřní parapet - materiál: Vlhkuodolná DTD; Horní podlaží: 1.NP
I.OH01 | Půdorys 1.NP | 0.75 | 1.5 | WINDOW |  | 0 | 2.2 | I.OH01 | MainObject | SmartPartCompressed | Izolační trojsklo 4-18-4-18-4 | 100 | 3.0 | Hliníkový profil 95 mm | Hliníkový profil | Lak bílý hliník - RAL 9006 | Hliníkový profil | Pákový ovladač | není | Celoobvodové kování | Jednokřídlové okno sklápěcí | 1464Obj1096174655 | Kus | Okno - objekt+SmartPart | 0.6076 | 80 | 80 | 80 | 0.8 | no | 0.75 | 1.5 | 1.125 | Pset_WindowCommon - Status: NEW; SecurityRating: bez; NEMSOK - Kód prvku: ON03.03.1001; Podlaží: 1.NP; Součinitel prostupu tepla - zasklení (Ug): Ug 0,6; Typ otevírání: Jednokřídlové okno sklápěcí; Solární faktor: 0.52; Světelný činitel prostupu: 0.74; Průvzdušnost: 4; Zasklení: Izolační trojsklo 4-18-4-18-4; Připojení EZS: Ano; Připojení NN: Ne; Připojení EPS: Ne; Připojení MaR: Ne; Vnitřní parapet - materiál: Vlhkuodolná DTD; Horní podlaží: 1.NP
I.OH01 | Půdorys 1.NP | 0.75 | 1.5 | WINDOW |  | 0 | 2.2 | I.OH01 | MainObject | SmartPartCompressed | Izolační trojsklo 4-18-4-18-4 | 100 | 3.0 | Hliníkový profil 95 mm | Hliníkový profil | Lak bílý hliník - RAL 9006 | Hliníkový profil | Pákový ovladač | není | Celoobvodové kování | Jednokřídlové okno sklápěcí | 1464Obj1096167692 | Kus | Okno - objekt+SmartPart | 0.6076 | 80 | 80 | 80 | 0.8 | no | 0.75 | 1.5 | 1.125 | Pset_WindowCommon - Status: NEW; SecurityRating: bez; NEMSOK - Kód prvku: ON03.03.1001; Podlaží: 1.NP; Součinitel prostupu tepla - zasklení (Ug): Ug 0,6; Typ otevírání: Jednokřídlové okno sklápěcí; Solární faktor: 0.52; Světelný činitel prostupu: 0.74; Průvzdušnost: 4; Zasklení: Izolační trojsklo 4-18-4-18-4; Připojení EZS: Ano; Připojení NN: Ne; Připojení EPS: Ne; Připojení MaR: Ne; Vnitřní parapet - materiál: Vlhkuodolná DTD; Horní podlaží: 1.NP
I.OH01 | Půdorys 1.NP | 0.75 | 1.5 | WINDOW |  | 0 | 2.2 | I.OH01 | MainObject | SmartPartCompressed | Izolační trojsklo 4-18-4-18-4 | 100 | 3.0 | Hliníkový profil 95 mm | Hliníkový profil | Lak bílý hliník - RAL 9006 | Hliníkový profil | Pákový ovladač | není | Celoobvodové kování | Jednokřídlové okno sklápěcí | 1464Obj1096168835 | Kus | Okno - objekt+SmartPart | 0.6076 | 80 | 80 | 80 | 0.8 | no | 0.75 | 1.5 | 1.125 | Pset_WindowCommon - Status: NEW; SecurityRating: bez; NEMSOK - Kód prvku: ON03.03.1001; Podlaží: 1.NP; Součinitel prostupu tepla - zasklení (Ug): Ug 0,6; Typ otevírání: Jednokřídlové okno sklápěcí; Solární faktor: 0.52; Světelný činitel prostupu: 0.74; Průvzdušnost: 4; Zasklení: Izolační trojsklo 4-18-4-18-4; Připojení EZS: Ano; Připojení NN: Ne; Připojení EPS: Ne; Připojení MaR: Ne; Vnitřní parapet - materiál: Vlhkuodolná DTD; Horní podlaží: 1.NP
I.OH01 | Půdorys 1.NP | 0.75 | 1.5 | WINDOW |  | 0 | 2.2 | I.OH01 | MainObject | SmartPartCompressed | Izolační trojsklo 4-18-4-18-4 | 100 | 3.0 | Hliníkový profil 95 mm | Hliníkový profil | Lak bílý hliník - RAL 9006 | Hliníkový profil | Pákový ovladač | není | Celoobvodové kování | Jednokřídlové okno sklápěcí | 1464Obj1096168855 | Kus | Okno - objekt+SmartPart | 0.6076 | 80 | 80 | 80 | 0.8 | no | 0.75 | 1.5 | 1.125 | Pset_WindowCommon - Status: NEW; SecurityRating: bez; NEMSOK - Kód prvku: ON03.03.1001; Podlaží: 1.NP; Součinitel prostupu tepla - zasklení (Ug): Ug 0,6; Typ otevírání: Jednokřídlové okno sklápěcí; Solární faktor: 0.52; Světelný činitel prostupu: 0.74; Průvzdušnost: 4; Zasklení: Izolační trojsklo 4-18-4-18-4; Připojení EZS: Ano; Připojení NN: Ne; Připojení EPS: Ne; Připojení MaR: Ne; Vnitřní parapet - materiál: Vlhkuodolná DTD; Horní podlaží: 1.NP
I.OH01 | Půdorys 1.NP | 0.75 | 1.5 | WINDOW |  | 0 | 2.2 | I.OH01 | MainObject | SmartPartCompressed | Izolační trojsklo 4-18-4-18-4 | 100 | 3.0 | Hliníkový profil 95 mm | Hliníkový profil | Lak bílý hliník - RAL 9006 | Hliníkový profil | Pákový ovladač | není | Celoobvodové kování | Jednokřídlové okno sklápěcí | 1464Obj1096168897 | Kus | Okno - objekt+SmartPart | 0.6076 | 80 | 80 | 80 | 0.8 | no | 0.75 | 1.5 | 1.125 | Pset_WindowCommon - Status: NEW; SecurityRating: bez; NEMSOK - Kód prvku: ON03.03.1001; Podlaží: 1.NP; Součinitel prostupu tepla - zasklení (Ug): Ug 0,6; Typ otevírání: Jednokřídlové okno sklápěcí; Solární faktor: 0.52; Světelný činitel prostupu: 0.74; Průvzdušnost: 4; Zasklení: Izolační trojsklo 4-18-4-18-4; Připojení EZS: Ano; Připojení NN: Ne; Připojení EPS: Ne; Připojení MaR: Ne; Vnitřní parapet - materiál: Vlhkuodolná DTD; Horní podlaží: 1.NP
I.OH01 | Půdorys 1.NP | 0.75 | 1.5 | WINDOW |  | 0 | 2.2 | I.OH01 | MainObject | SmartPartCompressed | Izolační trojsklo 4-18-4-18-4 | 100 | 3.0 | Hliníkový profil 95 mm | Hliníkový profil | Lak bílý hliník - RAL 9006 | Hliníkový profil | Pákový ovladač | není | Celoobvodové kování | Jednokřídlové okno sklápěcí | 1464Obj1096168928 | Kus | Okno - objekt+SmartPart | 0.6076 | 80 | 80 | 80 | 0.8 | no | 0.75 | 1.5 | 1.125 | Pset_WindowCommon - Status: NEW; SecurityRating: bez; NEMSOK - Kód prvku: ON03.03.1001; Podlaží: 1.NP; Součinitel prostupu tepla - zasklení (Ug): Ug 0,6; Typ otevírání: Jednokřídlové okno sklápěcí; Solární faktor: 0.52; Světelný činitel prostupu: 0.74; Průvzdušnost: 4; Zasklení: Izolační trojsklo 4-18-4-18-4; Připojení EZS: Ano; Připojení NN: Ne; Připojení EPS: Ne; Připojení MaR: Ne; Vnitřní parapet - materiál: Vlhkuodolná DTD; Horní podlaží: 1.NP
I.OH01 | Půdorys 1.NP | 0.75 | 1.5 | WINDOW |  | 0 | 2.2 | I.OH01 | MainObject | SmartPartCompressed | Izolační trojsklo 4-18-4-18-4 | 100 | 3.0 | Hliníkový profil 95 mm | Hliníkový profil | Lak bílý hliník - RAL 9006 | Hliníkový profil | Pákový ovladač | není | Celoobvodové kování | Jednokřídlové okno sklápěcí | 1464Obj1096168126 | Kus | Okno - objekt+SmartPart | 0.6076 | 80 | 80 | 80 | 0.8 | no | 0.75 | 1.5 | 1.125 | Pset_WindowCommon - Status: NEW; SecurityRating: bez; NEMSOK - Kód prvku: ON03.03.1001; Podlaží: 1.NP; Součinitel prostupu tepla - zasklení (Ug): Ug 0,6; Typ otevírání: Jednokřídlové okno sklápěcí; Solární faktor: 0.52; Světelný činitel prostupu: 0.74; Průvzdušnost: 4; Zasklení: Izolační trojsklo 4-18-4-18-4; Připojení EZS: Ano; Připojení NN: Ne; Připojení EPS: Ne; Připojení MaR: Ne; Vnitřní parapet - materiál: Vlhkuodolná DTD; Horní podlaží: 1.NP
I.OH01 | Půdorys 1.NP | 0.75 | 1.5 | WINDOW |  | 0 | 2.2 | I.OH01 | MainObject | SmartPartCompressed | Izolační trojsklo 4-18-4-18-4 | 100 | 3.0 | Hliníkový profil 95 mm | Hliníkový profil | Lak bílý hliník - RAL 9006 | Hliníkový profil | Pákový ovladač | není | Celoobvodové kování | Jednokřídlové okno sklápěcí | 1464Obj1096168157 | Kus | Okno - objekt+SmartPart | 0.6076 | 80 | 80 | 80 | 0.8 | no | 0.75 | 1.5 | 1.125 | Pset_WindowCommon - Status: NEW; SecurityRating: bez; NEMSOK - Kód prvku: ON03.03.1001; Podlaží: 1.NP; Součinitel prostupu tepla - zasklení (Ug): Ug 0,6; Typ otevírání: Jednokřídlové okno sklápěcí; Solární faktor: 0.52; Světelný činitel prostupu: 0.74; Průvzdušnost: 4; Zasklení: Izolační trojsklo 4-18-4-18-4; Připojení EZS: Ano; Připojení NN: Ne; Připojení EPS: Ne; Připojení MaR: Ne; Vnitřní parapet - materiál: Vlhkuodolná DTD; Horní podlaží: 1.NP
I.Z6 | Půdorys 1.NP | 1.2 | 0.6 | WINDOW |  | 0 | 2.2 | I.Z6 | MainObject | SmartPartCompressed |  | 100 | 3.0 | Dřevěný rám 92 mm | Dřevěný lepený eurohranol | Bílý lak | Dřevěný lepený eurohranol | Okenní klika | není | Celoobvodové kování s pětibodovým uzávěrem | Bemerkung mit max 254Zeichen | 1464Obj1096313495 | Kus | Okno - objekt+SmartPart | 0 | 20 | 20 | 20 | 0.8 | no | 1.2 | 0.6 | 0.72 | Pset_WindowCommon - SecurityRating: SA
I.Z6 | Půdorys 1.NP | 1.2 | 0.6 | WINDOW |  | 0 | 2.2 | I.Z6 | MainObject | SmartPartCompressed |  | 100 | 3.0 | Dřevěný rám 92 mm | Dřevěný lepený eurohranol | Bílý lak | Dřevěný lepený eurohranol | Okenní klika | není | Celoobvodové kování s pětibodovým uzávěrem | Bemerkung mit max 254Zeichen | 1464Obj1096313502 | Kus | Okno - objekt+SmartPart | 0 | 20 | 20 | 20 | 0.8 | no | 1.2 | 0.6 | 0.72 | Pset_WindowCommon - SecurityRating: SA
I.Z6 | Půdorys 1.NP | 0.4 | 0.4 | WINDOW |  | 0 | 2.2 | I.Z6 | MainObject | SmartPartCompressed |  | 100 | 3.0 | Dřevěný rám 92 mm | Dřevěný lepený eurohranol | Bílý lak | Dřevěný lepený eurohranol | Okenní klika | není | Celoobvodové kování s pětibodovým uzávěrem | Bemerkung mit max 254Zeichen | 1464Obj1096313506 | Kus | Okno - objekt+SmartPart | 0 | 20 | 20 | 20 | 0.8 | no | 0.4 | 0.4 | 0.16 | Pset_WindowCommon - SecurityRating: SA
O06 | Půdorys 2.NP | 2.1 | 1.5 | WINDOW | 0 | 0 | 2.2 | O06 | MainObject | SmartPartCompressed | Izolační trojsklo 4-18-4-18-4 Ug 0,5 | 100 | 3.0 | Dřevěný rám 92 mm | Dřevěný lepený eurohranol | Bílý lak | Dřevěný lepený eurohranol | Okenní klika | není | Celoobvodové kování s pětibodovým uzávěrem | Dvojkřídlové okno otevíravé a sklápěcí, symetricky dělené s nadsvětlíkem | 1552Obj0798428403 | Kus | Okno - objekt+SmartPart | 2.0584 | 80 | 80 | 80 | 0.8 | no | 2.1 | 1.5 | 3.15
O06 | Půdorys 2.NP | 2.1 | 1.5 | WINDOW | 0 | 0 | 2.2 | O06 | MainObject | SmartPartCompressed | Izolační trojsklo 4-18-4-18-4 Ug 0,5 | 100 | 3.0 | Dřevěný rám 92 mm | Dřevěný lepený eurohranol | Bílý lak | Dřevěný lepený eurohranol | Okenní klika | není | Celoobvodové kování s pětibodovým uzávěrem | Dvojkřídlové okno otevíravé a sklápěcí, symetricky dělené s nadsvětlíkem | 1552Obj0798439734 | Kus | Okno - objekt+SmartPart | 2.0584 | 80 | 80 | 80 | 0.8 | no | 2.1 | 1.5 | 3.15
O06 | Půdorys 2.NP | 2.1 | 1.5 | WINDOW | 0 | 0 | 2.2 | O06 | MainObject | SmartPartCompressed | Izolační trojsklo 4-18-4-18-4 Ug 0,5 | 100 | 3.0 | Dřevěný rám 92 mm | Dřevěný lepený eurohranol | Bílý lak | Dřevěný lepený eurohranol | Okenní klika | není | Celoobvodové kování s pětibodovým uzávěrem | Dvojkřídlové okno otevíravé a sklápěcí, symetricky dělené s nadsvětlíkem | 1552Obj0798440172 | Kus | Okno - objekt+SmartPart | 2.0584 | 80 | 80 | 80 | 0.8 | no | 2.1 | 1.5 | 3.15
O06 | Půdorys 2.NP | 2.1 | 1.5 | WINDOW | 0 | 0 | 2.2 | O06 | MainObject | SmartPartCompressed | Izolační trojsklo 4-18-4-18-4 Ug 0,5 | 100 | 3.0 | Dřevěný rám 92 mm | Dřevěný lepený eurohranol | Bílý lak | Dřevěný lepený eurohranol | Okenní klika | není | Celoobvodové kování s pětibodovým uzávěrem | Dvojkřídlové okno otevíravé a sklápěcí, symetricky dělené s nadsvětlíkem | 1552Obj0798440288 | Kus | Okno - objekt+SmartPart | 2.0584 | 80 | 80 | 80 | 0.8 | no | 2.1 | 1.5 | 3.15
O06 | Půdorys 2.NP | 2.1 | 1.5 | WINDOW | 0 | 0 | 2.2 | O06 | MainObject | SmartPartCompressed | Izolační trojsklo 4-18-4-18-4 Ug 0,5 | 100 | 3.0 | Dřevěný rám 92 mm | Dřevěný lepený eurohranol | Bílý lak | Dřevěný lepený eurohranol | Okenní klika | není | Celoobvodové kování s pětibodovým uzávěrem | Dvojkřídlové okno otevíravé a sklápěcí, symetricky dělené s nadsvětlíkem | 1552Obj0798440279 | Kus | Okno - objekt+SmartPart | 2.0584 | 80 | 80 | 80 | 0.8 | no | 2.1 | 1.5 | 3.15
O06 | Půdorys 2.NP | 2.1 | 1.5 | WINDOW | 0 | 0 | 2.2 | O06 | MainObject | SmartPartCompressed | Izolační trojsklo 4-18-4-18-4 Ug 0,5 | 100 | 3.0 | Dřevěný rám 92 mm | Dřevěný lepený eurohranol | Bílý lak | Dřevěný lepený eurohranol | Okenní klika | není | Celoobvodové kování s pětibodovým uzávěrem | Dvojkřídlové okno otevíravé a sklápěcí, symetricky dělené s nadsvětlíkem | 1552Obj0798440270 | Kus | Okno - objekt+SmartPart | 2.0584 | 80 | 80 | 80 | 0.8 | no | 2.1 | 1.5 | 3.15
O06 | Půdorys 2.NP | 2.1 | 1.5 | WINDOW | 0 | 0 | 2.2 | O06 | MainObject | SmartPartCompressed | Izolační trojsklo 4-18-4-18-4 Ug 0,5 | 100 | 3.0 | Dřevěný rám 92 mm | Dřevěný lepený eurohranol | Bílý lak | Dřevěný lepený eurohranol | Okenní klika | není | Celoobvodové kování s pětibodovým uzávěrem | Dvojkřídlové okno otevíravé a sklápěcí, symetricky dělené s nadsvětlíkem | 1552Obj0798440261 | Kus | Okno - objekt+SmartPart | 2.0584 | 80 | 80 | 80 | 0.8 | no | 2.1 | 1.5 | 3.15
O06 | Půdorys 2.NP | 2.1 | 1.5 | WINDOW | 0 | 0 | 2.2 | O06 | MainObject | SmartPartCompressed | Izolační trojsklo 4-18-4-18-4 Ug 0,5 | 100 | 3.0 | Dřevěný rám 92 mm | Dřevěný lepený eurohranol | Bílý lak | Dřevěný lepený eurohranol | Okenní klika | není | Celoobvodové kování s pětibodovým uzávěrem | Dvojkřídlové okno otevíravé a sklápěcí, symetricky dělené s nadsvětlíkem | 1552Obj0798440252 | Kus | Okno - objekt+SmartPart | 2.0584 | 80 | 80 | 80 | 0.8 | no | 2.1 | 1.5 | 3.15
O06 | Půdorys 2.NP | 2.1 | 1.5 | WINDOW | 0 | 0 | 2.2 | O06 | MainObject | SmartPartCompressed | Izolační trojsklo 4-18-4-18-4 Ug 0,5 | 100 | 3.0 | Dřevěný rám 92 mm | Dřevěný lepený eurohranol | Bílý lak | Dřevěný lepený eurohranol | Okenní klika | není | Celoobvodové kování s pětibodovým uzávěrem | Dvojkřídlové okno otevíravé a sklápěcí, symetricky dělené s nadsvětlíkem | 1552Obj0798440243 | Kus | Okno - objekt+SmartPart | 2.0584 | 80 | 80 | 80 | 0.8 | no | 2.1 | 1.5 | 3.15
O06 | Půdorys 2.NP | 2.1 | 1.5 | WINDOW | 0 | 0 | 2.2 | O06 | MainObject | SmartPartCompressed | Izolační trojsklo 4-18-4-18-4 Ug 0,5 | 100 | 3.0 | Dřevěný rám 92 mm | Dřevěný lepený eurohranol | Bílý lak | Dřevěný lepený eurohranol | Okenní klika | není | Celoobvodové kování s pětibodovým uzávěrem | Dvojkřídlové okno otevíravé a sklápěcí, symetricky dělené s nadsvětlíkem | 1552Obj0798440234 | Kus | Okno - objekt+SmartPart | 2.0584 | 80 | 80 | 80 | 0.8 | no | 2.1 | 1.5 | 3.15
O06 | Půdorys 2.NP | 2.1 | 1.5 | WINDOW | 0 | 0 | 2.2 | O06 | MainObject | SmartPartCompressed | Izolační trojsklo 4-18-4-18-4 Ug 0,5 | 100 | 3.0 | Dřevěný rám 92 mm | Dřevěný lepený eurohranol | Bílý lak | Dřevěný lepený eurohranol | Okenní klika | není | Celoobvodové kování s pětibodovým uzávěrem | Dvojkřídlové okno otevíravé a sklápěcí, symetricky dělené s nadsvětlíkem | 1552Obj0798437491 | Kus | Okno - objekt+SmartPart | 2.0584 | 80 | 80 | 80 | 0.8 | no | 2.1 | 1.5 | 3.15
O06 | Půdorys 2.NP | 2.1 | 1.5 | WINDOW | 0 | 0 | 2.2 | O06 | MainObject | SmartPartCompressed | Izolační trojsklo 4-18-4-18-4 Ug 0,5 | 100 | 3.0 | Dřevěný rám 92 mm | Dřevěný lepený eurohranol | Bílý lak | Dřevěný lepený eurohranol | Okenní klika | není | Celoobvodové kování s pětibodovým uzávěrem | Dvojkřídlové okno otevíravé a sklápěcí, symetricky dělené s nadsvětlíkem | 1552Obj0798438824 | Kus | Okno - objekt+SmartPart | 2.0584 | 80 | 80 | 80 | 0.8 | no | 2.1 | 1.5 | 3.15
O06 | Půdorys 2.NP | 2.1 | 1.5 | WINDOW | 0 | 0 | 2.2 | O06 | MainObject | SmartPartCompressed | Izolační trojsklo 4-18-4-18-4 Ug 0,5 | 100 | 3.0 | Dřevěný rám 92 mm | Dřevěný lepený eurohranol | Bílý lak | Dřevěný lepený eurohranol | Okenní klika | není | Celoobvodové kování s pětibodovým uzávěrem | Dvojkřídlové okno otevíravé a sklápěcí, symetricky dělené s nadsvětlíkem | 1552Obj0798438895 | Kus | Okno - objekt+SmartPart | 2.0584 | 80 | 80 | 80 | 0.8 | no | 2.1 | 1.5 | 3.15
O06 | Půdorys 2.NP | 2.1 | 1.5 | WINDOW | 0 | 0 | 2.2 | O06 | MainObject | SmartPartCompressed | Izolační trojsklo 4-18-4-18-4 Ug 0,5 | 100 | 3.0 | Dřevěný rám 92 mm | Dřevěný lepený eurohranol | Bílý lak | Dřevěný lepený eurohranol | Okenní klika | není | Celoobvodové kování s pětibodovým uzávěrem | Dvojkřídlové okno otevíravé a sklápěcí, symetricky dělené s nadsvětlíkem | 1552Obj0798438886 | Kus | Okno - objekt+SmartPart | 2.0584 | 80 | 80 | 80 | 0.8 | no | 2.1 | 1.5 | 3.15
O06 | Půdorys 2.NP | 2.1 | 1.5 | WINDOW | 0 | 0 | 2.2 | O06 | MainObject | SmartPartCompressed | Izolační trojsklo 4-18-4-18-4 Ug 0,5 | 100 | 3.0 | Dřevěný rám 92 mm | Dřevěný lepený eurohranol | Bílý lak | Dřevěný lepený eurohranol | Okenní klika | není | Celoobvodové kování s pětibodovým uzávěrem | Dvojkřídlové okno otevíravé a sklápěcí, symetricky dělené s nadsvětlíkem | 1552Obj0798437032 | Kus | Okno - objekt+SmartPart | 2.0584 | 80 | 80 | 80 | 0.8 | no | 2.1 | 1.5 | 3.15
O06 | Půdorys 2.NP | 2.1 | 1.5 | WINDOW | 0 | 0 | 2.2 | O06 | MainObject | SmartPartCompressed | Izolační trojsklo 4-18-4-18-4 Ug 0,5 | 100 | 3.0 | Dřevěný rám 92 mm | Dřevěný lepený eurohranol | Bílý lak | Dřevěný lepený eurohranol | Okenní klika | není | Celoobvodové kování s pětibodovým uzávěrem | Dvojkřídlové okno otevíravé a sklápěcí, symetricky dělené s nadsvětlíkem | 1552Obj0798437018 | Kus | Okno - objekt+SmartPart | 2.0584 | 80 | 80 | 80 | 0.8 | no | 2.1 | 1.5 | 3.15
O06 | Půdorys 2.NP | 2.1 | 1.5 | WINDOW | 0 | 0 | 2.2 | O06 | MainObject | SmartPartCompressed | Izolační trojsklo 4-18-4-18-4 Ug 0,5 | 100 | 3.0 | Dřevěný rám 92 mm | Dřevěný lepený eurohranol | Bílý lak | Dřevěný lepený eurohranol | Okenní klika | není | Celoobvodové kování s pětibodovým uzávěrem | Dvojkřídlové okno otevíravé a sklápěcí, symetricky dělené s nadsvětlíkem | 1552Obj0798436927 | Kus | Okno - objekt+SmartPart | 2.0584 | 80 | 80 | 80 | 0.8 | no | 2.1 | 1.5 | 3.15
O06 | Půdorys 2.NP | 2.1 | 1.5 | WINDOW | 0 | 0 | 2.2 | O06 | MainObject | SmartPartCompressed | Izolační trojsklo 4-18-4-18-4 Ug 0,5 | 100 | 3.0 | Dřevěný rám 92 mm | Dřevěný lepený eurohranol | Bílý lak | Dřevěný lepený eurohranol | Okenní klika | není | Celoobvodové kování s pětibodovým uzávěrem | Dvojkřídlové okno otevíravé a sklápěcí, symetricky dělené s nadsvětlíkem | 1552Obj0798436493 | Kus | Okno - objekt+SmartPart | 2.0584 | 80 | 80 | 80 | 0.8 | no | 2.1 | 1.5 | 3.15
O06 | Půdorys 2.NP | 2.1 | 1.5 | WINDOW | 0 | 0 | 2.2 | O06 | MainObject | SmartPartCompressed | Izolační trojsklo 4-18-4-18-4 Ug 0,5 | 100 | 3.0 | Dřevěný rám 92 mm | Dřevěný lepený eurohranol | Bílý lak | Dřevěný lepený eurohranol | Okenní klika | není | Celoobvodové kování s pětibodovým uzávěrem | Dvojkřídlové okno otevíravé a sklápěcí, symetricky dělené s nadsvětlíkem | 1552Obj0798436485 | Kus | Okno - objekt+SmartPart | 2.0584 | 80 | 80 | 80 | 0.8 | no | 2.1 | 1.5 | 3.15
O06 | Půdorys 2.NP | 2.1 | 1.5 | WINDOW | 0 | 0 | 2.2 | O06 | MainObject | SmartPartCompressed | Izolační trojsklo 4-18-4-18-4 Ug 0,5 | 100 | 3.0 | Dřevěný rám 92 mm | Dřevěný lepený eurohranol | Bílý lak | Dřevěný lepený eurohranol | Okenní klika | není | Celoobvodové kování s pětibodovým uzávěrem | Dvojkřídlové okno otevíravé a sklápěcí, symetricky dělené s nadsvětlíkem | 1552Obj0798436477 | Kus | Okno - objekt+SmartPart | 2.0584 | 80 | 80 | 80 | 0.8 | no | 2.1 | 1.5 | 3.15
O06 | Půdorys 2.NP | 2.1 | 1.2 | WINDOW | 0 | 0 | 2.2 | O06 | MainObject | SmartPartCompressed | Izolační trojsklo 4-18-4-18-4 Ug 0,5 | 100 | 3.0 | Dřevěný rám 92 mm | Dřevěný lepený eurohranol | Bílý lak | Dřevěný lepený eurohranol | Okenní klika | není | Celoobvodové kování s pětibodovým uzávěrem | Dvojkřídlové okno otevíravé a sklápěcí, symetricky dělené s nadsvětlíkem | 1552Obj0798436535 | Kus | Okno - objekt+SmartPart | 1.5604 | 80 | 80 | 80 | 0.8 | no | 2.1 | 1.2 | 2.52
O06 | Půdorys 2.NP | 2.1 | 1.2 | WINDOW | 0 | 0 | 2.2 | O06 | MainObject | SmartPartCompressed | Izolační trojsklo 4-18-4-18-4 Ug 0,5 | 100 | 3.0 | Dřevěný rám 92 mm | Dřevěný lepený eurohranol | Bílý lak | Dřevěný lepený eurohranol | Okenní klika | není | Celoobvodové kování s pětibodovým uzávěrem | Dvojkřídlové okno otevíravé a sklápěcí, symetricky dělené s nadsvětlíkem | 1552Obj0798436577 | Kus | Okno - objekt+SmartPart | 1.5604 | 80 | 80 | 80 | 0.8 | no | 2.1 | 1.2 | 2.52
O06 | Půdorys 2.NP | 2.1 | 1.2 | WINDOW | 0 | 0 | 2.2 | O06 | MainObject | SmartPartCompressed | Izolační trojsklo 4-18-4-18-4 Ug 0,5 | 100 | 3.0 | Dřevěný rám 92 mm | Dřevěný lepený eurohranol | Bílý lak | Dřevěný lepený eurohranol | Okenní klika | není | Celoobvodové kování s pětibodovým uzávěrem | Dvojkřídlové okno otevíravé a sklápěcí, symetricky dělené s nadsvětlíkem | 1552Obj0798436585 | Kus | Okno - objekt+SmartPart | 1.5604 | 80 | 80 | 80 | 0.8 | no | 2.1 | 1.2 | 2.52
O06 | Půdorys 2.NP | 2.1 | 1.2 | WINDOW | 0 | 0 | 2.2 | O06 | MainObject | SmartPartCompressed | Izolační trojsklo 4-18-4-18-4 Ug 0,5 | 100 | 3.0 | Dřevěný rám 92 mm | Dřevěný lepený eurohranol | Bílý lak | Dřevěný lepený eurohranol | Okenní klika | není | Celoobvodové kování s pětibodovým uzávěrem | Dvojkřídlové okno otevíravé a sklápěcí, symetricky dělené s nadsvětlíkem | 1552Obj0798436435 | Kus | Okno - objekt+SmartPart | 1.5604 | 80 | 80 | 80 | 0.8 | no | 2.1 | 1.2 | 2.52
O06 | Půdorys 2.NP | 1.5 | 1.5 | WINDOW | 0 | 0 | 2.2 | O06 | MainObject | SmartPartCompressed | Izolační trojsklo 4-18-4-18-4 Ug 0,5 | 100 | 3.0 | Dřevěný rám 92 mm | Dřevěný lepený eurohranol | Bílý lak | Dřevěný lepený eurohranol | Okenní klika | není | Celoobvodové kování s pětibodovým uzávěrem | Dvojkřídlové okno otevíravé a sklápěcí, symetricky dělené s nadsvětlíkem | 1552Obj0798440848 | Kus | Okno - objekt+SmartPart | 1.5376 | 80 | 80 | 80 | 0.8 | no | 1.5 | 1.5 | 2.25
O06 | Půdorys 2.NP | 1.5 | 1.5 | WINDOW | 0 | 0 | 2.2 | O06 | MainObject | SmartPartCompressed | Izolační trojsklo 4-18-4-18-4 Ug 0,5 | 100 | 3.0 | Dřevěný rám 92 mm | Dřevěný lepený eurohranol | Bílý lak | Dřevěný lepený eurohranol | Okenní klika | není | Celoobvodové kování s pětibodovým uzávěrem | Dvojkřídlové okno otevíravé a sklápěcí, symetricky dělené s nadsvětlíkem | 1552Obj0798440943 | Kus | Okno - objekt+SmartPart | 1.5376 | 80 | 80 | 80 | 0.8 | no | 1.5 | 1.5 | 2.25
O06 | Půdorys 2.NP | 2.15 | 1.2 | WINDOW | 0 | 0 | 2.2 | O06 | MainObject | SmartPartCompressed | Izolační trojsklo 4-18-4-18-4 Ug 0,5 | 100 | 3.0 | Dřevěný rám 92 mm | Dřevěný lepený eurohranol | Bílý lak | Dřevěný lepený eurohranol | Okenní klika | není | Celoobvodové kování s pětibodovým uzávěrem | Dvojkřídlové okno otevíravé a sklápěcí, symetricky dělené s nadsvětlíkem | 1552Obj0798426013 | Kus | Okno - objekt+SmartPart | 1.6074 | 80 | 80 | 80 | 0.8 | no | 2.15 | 1.2 | 2.58
O01 | Půdorys 2.NP | 1.2 | 0.6 | WINDOW | 0 | 0 | 2.2 | O01 | MainObject | SmartPartCompressed |  | 100 | 3.0 | Dřevěný rám 92 mm | Dřevěný lepený eurohranol | Bílý lak | Dřevěný lepený eurohranol | Okenní klika | není | Celoobvodové kování s pětibodovým uzávěrem |  | 1552Obj0798441501 | Kus | Okno - objekt+SmartPart | 0 | 20 | 20 | 20 | 0.8 | no | 1.2 | 0.6 | 0.72
O01 | Půdorys 2.NP | 1.2 | 0.6 | WINDOW | 0 | 0 | 2.2 | O01 | MainObject | SmartPartCompressed |  | 100 | 3.0 | Dřevěný rám 92 mm | Dřevěný lepený eurohranol | Bílý lak | Dřevěný lepený eurohranol | Okenní klika | není | Celoobvodové kování s pětibodovým uzávěrem |  | 1552Obj0798443581 | Kus | Okno - objekt+SmartPart | 0 | 20 | 20 | 20 | 0.8 | no | 1.2 | 0.6 | 0.72
O01 | Půdorys 2.NP | 1.2 | 0.6 | WINDOW | 0 | 0 | 2.2 | O01 | MainObject | SmartPartCompressed |  | 100 | 3.0 | Dřevěný rám 92 mm | Dřevěný lepený eurohranol | Bílý lak | Dřevěný lepený eurohranol | Okenní klika | není | Celoobvodové kování s pětibodovým uzávěrem |  | 1552Obj0798443121 | Kus | Okno - objekt+SmartPart | 0 | 20 | 20 | 20 | 0.8 | no | 1.2 | 0.6 | 0.72
O01 | Půdorys 2.NP | 1.2 | 0.6 | WINDOW | 0 | 0 | 2.2 | O01 | MainObject | SmartPartCompressed |  | 100 | 3.0 | Dřevěný rám 92 mm | Dřevěný lepený eurohranol | Bílý lak | Dřevěný lepený eurohranol | Okenní klika | není | Celoobvodové kování s pětibodovým uzávěrem |  | 1552Obj0798443156 | Kus | Okno - objekt+SmartPart | 0 | 20 | 20 | 20 | 0.8 | no | 1.2 | 0.6 | 0.72
O01 | Půdorys 2.NP | 1.2 | 0.6 | WINDOW | 0 | 0 | 2.2 | O01 | MainObject | SmartPartCompressed |  | 100 | 3.0 | Dřevěný rám 92 mm | Dřevěný lepený eurohranol | Bílý lak | Dřevěný lepený eurohranol | Okenní klika | není | Celoobvodové kování s pětibodovým uzávěrem |  | 1552Obj0798454320 | Kus | Okno - objekt+SmartPart | 0 | 20 | 20 | 20 | 0.8 | no | 1.2 | 0.6 | 0.72
O01 | Půdorys 2.NP | 1.2 | 0.6 | WINDOW | 0 | 0 | 2.2 | O01 | MainObject | SmartPartCompressed |  | 100 | 3.0 | Dřevěný rám 92 mm | Dřevěný lepený eurohranol | Bílý lak | Dřevěný lepený eurohranol | Okenní klika | není | Celoobvodové kování s pětibodovým uzávěrem |  | 1552Obj0798443934 | Kus | Okno - objekt+SmartPart | 0 | 20 | 20 | 20 | 0.8 | no | 1.2 | 0.6 | 0.72
O01 | Půdorys 2.NP | 1.2 | 0.6 | WINDOW | 0 | 0 | 2.2 | O01 | MainObject | SmartPartCompressed |  | 100 | 3.0 | Dřevěný rám 92 mm | Dřevěný lepený eurohranol | Bílý lak | Dřevěný lepený eurohranol | Okenní klika | není | Celoobvodové kování s pětibodovým uzávěrem |  | 1552Obj0798443949 | Kus | Okno - objekt+SmartPart | 0 | 20 | 20 | 20 | 0.8 | no | 1.2 | 0.6 | 0.72
O06 | Půdorys 2.NP | 2.1 | 2.4 | WINDOW | 0 | 0 | 2.2 | O06 | MainObject | SmartPartCompressed | Izolační trojsklo 4-18-4-18-4 Ug 0,5 | 100 | 3.0 | Dřevěný rám 92 mm | Dřevěný lepený eurohranol | Bílý lak | Dřevěný lepený eurohranol | Okenní klika | není | Celoobvodové kování s pětibodovým uzávěrem | Dvojkřídlové okno otevíravé a sklápěcí, symetricky dělené s nadsvětlíkem | 1552Obj0798440347 | Kus | Okno - objekt+SmartPart | 3.2536 | 80 | 80 | 80 | 0.8 | no | 2.1 | 2.4 | 5.04
O06 | Půdorys 2.NP | 2.1 | 2.4 | WINDOW | 0 | 0 | 2.2 | O06 | MainObject | SmartPartCompressed | Izolační trojsklo 4-18-4-18-4 Ug 0,5 | 100 | 3.0 | Dřevěný rám 92 mm | Dřevěný lepený eurohranol | Bílý lak | Dřevěný lepený eurohranol | Okenní klika | není | Celoobvodové kování s pětibodovým uzávěrem | Dvojkřídlové okno otevíravé a sklápěcí, symetricky dělené s nadsvětlíkem | 1552Obj0798440469 | Kus | Okno - objekt+SmartPart | 3.2536 | 80 | 80 | 80 | 0.8 | no | 2.1 | 2.4 | 5.04
O06 | Půdorys 2.NP | 2.1 | 1.5 | WINDOW | 0 | 0 | 2.2 | O06 | MainObject | SmartPartCompressed | Izolační trojsklo 4-18-4-18-4 Ug 0,5 | 100 | 3.0 | Dřevěný rám 92 mm | Dřevěný lepený eurohranol | Bílý lak | Dřevěný lepený eurohranol | Okenní klika | není | Celoobvodové kování s pětibodovým uzávěrem | Dvojkřídlové okno otevíravé a sklápěcí, symetricky dělené s nadsvětlíkem | 1552Obj0798440549 | Kus | Okno - objekt+SmartPart | 2.0584 | 80 | 80 | 80 | 0.8 | no | 2.1 | 1.5 | 3.15
O06 | Půdorys 2.NP | 2.1 | 1.5 | WINDOW | 0 | 0 | 2.2 | O06 | MainObject | SmartPartCompressed | Izolační trojsklo 4-18-4-18-4 Ug 0,5 | 100 | 3.0 | Dřevěný rám 92 mm | Dřevěný lepený eurohranol | Bílý lak | Dřevěný lepený eurohranol | Okenní klika | není | Celoobvodové kování s pětibodovým uzávěrem | Dvojkřídlové okno otevíravé a sklápěcí, symetricky dělené s nadsvětlíkem | 1552Obj0798440540 | Kus | Okno - objekt+SmartPart | 2.0584 | 80 | 80 | 80 | 0.8 | no | 2.1 | 1.5 | 3.15
O06 | Půdorys 2.NP | 2.1 | 1.5 | WINDOW | 0 | 0 | 2.2 | O06 | MainObject | SmartPartCompressed | Izolační trojsklo 4-18-4-18-4 Ug 0,5 | 100 | 3.0 | Dřevěný rám 92 mm | Dřevěný lepený eurohranol | Bílý lak | Dřevěný lepený eurohranol | Okenní klika | není | Celoobvodové kování s pětibodovým uzávěrem | Dvojkřídlové okno otevíravé a sklápěcí, symetricky dělené s nadsvětlíkem | 1552Obj0798440531 | Kus | Okno - objekt+SmartPart | 2.0584 | 80 | 80 | 80 | 0.8 | no | 2.1 | 1.5 | 3.15
O06 | Půdorys 2.NP | 1.25 | 0.6 | WINDOW | 0 | 0 | 2.2 | O06 | MainObject | SmartPartCompressed | Izolační trojsklo 4-18-4-18-4 Ug 0,5 | 100 | 3.0 | Dřevěný rám 92 mm | Dřevěný lepený eurohranol | Bílý lak | Dřevěný lepený eurohranol | Okenní klika | není | Celoobvodové kování s pětibodovým uzávěrem | Dvojkřídlové okno otevíravé a sklápěcí, symetricky dělené s nadsvětlíkem | 1552Obj0798440584 | Kus | Okno - objekt+SmartPart | 0.3366 | 80 | 80 | 80 | 0.8 | no | 1.25 | 0.6 | 0.75
O06 | Půdorys 2.NP | 1.25 | 0.6 | WINDOW | 0 | 0 | 2.2 | O06 | MainObject | SmartPartCompressed | Izolační trojsklo 4-18-4-18-4 Ug 0,5 | 100 | 3.0 | Dřevěný rám 92 mm | Dřevěný lepený eurohranol | Bílý lak | Dřevěný lepený eurohranol | Okenní klika | není | Celoobvodové kování s pětibodovým uzávěrem | Dvojkřídlové okno otevíravé a sklápěcí, symetricky dělené s nadsvětlíkem | 1552Obj0798440695 | Kus | Okno - objekt+SmartPart | 0.3366 | 80 | 80 | 80 | 0.8 | no | 1.25 | 0.6 | 0.75
O06 | Půdorys 2.NP | 1.25 | 0.6 | WINDOW | 0 | 0 | 2.2 | O06 | MainObject | SmartPartCompressed | Izolační trojsklo 4-18-4-18-4 Ug 0,5 | 100 | 3.0 | Dřevěný rám 92 mm | Dřevěný lepený eurohranol | Bílý lak | Dřevěný lepený eurohranol | Okenní klika | není | Celoobvodové kování s pětibodovým uzávěrem | Dvojkřídlové okno otevíravé a sklápěcí, symetricky dělené s nadsvětlíkem | 1552Obj0798440686 | Kus | Okno - objekt+SmartPart | 0.3366 | 80 | 80 | 80 | 0.8 | no | 1.25 | 0.6 | 0.75
O06 | Půdorys 2.NP | 1.25 | 0.6 | WINDOW | 0 | 0 | 2.2 | O06 | MainObject | SmartPartCompressed | Izolační trojsklo 4-18-4-18-4 Ug 0,5 | 100 | 3.0 | Dřevěný rám 92 mm | Dřevěný lepený eurohranol | Bílý lak | Dřevěný lepený eurohranol | Okenní klika | není | Celoobvodové kování s pětibodovým uzávěrem | Dvojkřídlové okno otevíravé a sklápěcí, symetricky dělené s nadsvětlíkem | 1552Obj0798440677 | Kus | Okno - objekt+SmartPart | 0.3366 | 80 | 80 | 80 | 0.8 | no | 1.25 | 0.6 | 0.75
O01 | Půdorys 2.NP | 1.2 | 0.6 | WINDOW | 0 | 0 | 2.2 | O01 | MainObject | SmartPartCompressed |  | 100 | 3.0 | Dřevěný rám 92 mm | Dřevěný lepený eurohranol | Bílý lak | Dřevěný lepený eurohranol | Okenní klika | není | Celoobvodové kování s pětibodovým uzávěrem |  | 1552Obj0798447224 | Kus | Okno - objekt+SmartPart | 0 | 20 | 20 | 20 | 0.8 | no | 1.2 | 0.6 | 0.72
O01 | Půdorys 2.NP | 1.2 | 0.6 | WINDOW | 0 | 0 | 2.2 | O01 | MainObject | SmartPartCompressed |  | 100 | 3.0 | Dřevěný rám 92 mm | Dřevěný lepený eurohranol | Bílý lak | Dřevěný lepený eurohranol | Okenní klika | není | Celoobvodové kování s pětibodovým uzávěrem |  | 1552Obj0798447218 | Kus | Okno - objekt+SmartPart | 0 | 20 | 20 | 20 | 0.8 | no | 1.2 | 0.6 | 0.72
O06 | Půdorys 2.NP | 2 | 1.5 | WINDOW | 0 | 0 | 2.2 | O06 | MainObject | SmartPartCompressed | Izolační trojsklo 4-18-4-18-4 Ug 0,5 | 100 | 3.0 | Dřevěný rám 92 mm | Dřevěný lepený eurohranol | Bílý lak | Dřevěný lepený eurohranol | Okenní klika | není | Celoobvodové kování s pětibodovým uzávěrem | Dvojkřídlové okno otevíravé a sklápěcí, symetricky dělené s nadsvětlíkem | 1552Obj0798450509 | Kus | Okno - objekt+SmartPart | 1.9344 | 80 | 80 | 80 | 0.8 | no | 2 | 1.5 | 3
I.OP11 | Půdorys 2.NP | 2.1 | 1.5 | WINDOW |  | 0 | 2.2 | I.OP11 | MainObject | SmartPartCompressed | Izolační trojsklo 4-18-4-18-4 | 100 | 3.0 | Plastový profil 82mm | Plasotvý profil | Barva bílá | Plastový profil | Okenní klika | není | Celoobvodové kování s pětibodovým uzávěrem | Dvojkřídlové okno, 1×otevíravé/sklopné, 1×sklopné | 1564Obj0798463289 | Kus | Okno - objekt+SmartPart | 2.0584 | 80 | 80 | 80 | 0.8 | no | 2.1 | 1.5 | 3.15 | Pset_WindowCommon - Status: NEW; SecurityRating: bez; NEMSOK - Kód prvku: ON04.04.0001; Podlaží: 2.NP; Součinitel prostupu tepla - zasklení (Ug): 0,6; Typ otevírání: Dvojkřídlové okno, 1×otevíravé/sklopné, 1×sklopné; Solární faktor: 0.52; Světelný činitel prostupu: 0.74; Průvzdušnost: 4; Zasklení: Izolační trojsklo 4-18-4-18-4; Připojení EZS: Ne; Připojení NN: Ne; Připojení EPS: Ne; Připojení MaR: Ne; Vnitřní parapet - materiál: Vlhkuodolná DTD
I.OP12 | Půdorys 2.NP | 2.12 | 2.8 | WINDOW |  | 0 | 2.2 | I.OP12 | MainObject | SmartPartCompressed | Izolační trojsklo 4-18-4-18-4 | 100 | 3.0 | Plastový profil 82mm | Plasotvý profil | Barva bílá | Plastový profil | Okenní klika | není | Celoobvodové kování s pětibodovým uzávěrem | Čtyřkřídlové okno, 2×otevíravé/sklopné, 2×sklopné | 1564Obj0798470324 | Kus | Okno - objekt+SmartPart | 3.9648 | 80 | 80 | 80 | 0.8 | no | 2.12 | 2.8 | 5.936 | Pset_WindowCommon - Status: NEW; SecurityRating: bez; NEMSOK - Kód prvku: ON04.04.0002; Podlaží: 2.NP; Součinitel prostupu tepla - zasklení (Ug): 0.6; Typ otevírání: Čtyřkřídlové okno, 2×otevíravé/sklopné, 2×sklopné; Solární faktor: 0.52; Světelný činitel prostupu: 0.74; Průvzdušnost: 4; Zasklení: Izolační trojsklo 4-18-4-18-4; Připojení EZS: Ne; Připojení NN: Ne; Připojení EPS: Ne; Připojení MaR: Ne; Vnitřní parapet - materiál: Vlhkuodolná DTD
Světlík | Půdorys 2.NP | 0.17944 | 0.34964 | SKYLIGHT |  |  | 2.2 | Světlík | MainObject | SmartPartCompressed |  |  | 2.1 |  |  |  |  |  |  |  |  | 1564Obj0798461905 | Kus | II.SV | NEMSOK - Kód prvku: OV00.04.2001; Výška_podstavy_světlíku: 0.3 m; Výška_kopule_světlíku: 0.16 m
Světlík | Půdorys 2.NP | 0.12886 | 0.34964 | SKYLIGHT |  |  | 2.2 | Světlík | MainObject | SmartPartCompressed |  |  | 2.1 |  |  |  |  |  |  |  |  | 1564Obj0798461896 | Kus | II.SV | NEMSOK - Kód prvku: OV00.04.2001; Výška_podstavy_světlíku: 0.3 m; Výška_kopule_světlíku: 0.16 m
Světlík | Půdorys 2.NP | 0.11969 | 0.34964 | SKYLIGHT |  |  | 2.2 | Světlík | MainObject | SmartPartCompressed |  |  | 2.1 |  |  |  |  |  |  |  |  | 1564Obj0798461887 | Kus | II.SV | NEMSOK - Kód prvku: OV00.04.2001; Výška_podstavy_světlíku: 0.3 m; Výška_kopule_světlíku: 0.16 m
Světlík | Půdorys 2.NP | 0.16229 | 0.34964 | SKYLIGHT |  |  | 2.2 | Světlík | MainObject | SmartPartCompressed |  |  | 2.1 |  |  |  |  |  |  |  |  | 1564Obj0798461878 | Kus | II.SV | NEMSOK - Kód prvku: OV00.04.2001; Výška_podstavy_světlíku: 0.3 m; Výška_kopule_světlíku: 0.16 m
Světlík | Půdorys 2.NP | 0.21274 | 0.34964 | SKYLIGHT |  |  | 2.2 | Světlík | MainObject | SmartPartCompressed |  |  | 2.1 |  |  |  |  |  |  |  |  | 1564Obj0798461844 | Kus | I.SV1 | NEMSOK - Kód prvku: OV00.04.1001; Výška_podstavy_světlíku: 0.3 m; Výška_kopule_světlíku: 0.16 m
Světlík | Půdorys 2.NP | 0.13669 | 0.34964 | SKYLIGHT |  |  | 2.2 | Světlík | MainObject | SmartPartCompressed |  |  | 2.1 |  |  |  |  |  |  |  |  | 1564Obj0798461869 | Kus | I.SV1 | NEMSOK - Kód prvku: OV00.04.1001; Výška_podstavy_světlíku: 0.3 m; Výška_kopule_světlíku: 0.16 m
Světlík | Půdorys 2.NP | 0.04999 | 0.34964 | SKYLIGHT |  |  | 2.2 | Světlík | MainObject | SmartPartCompressed |  |  | 2.1 |  |  |  |  |  |  |  |  | 1564Obj0798461812 | Kus | I.SV1 | NEMSOK - Kód prvku: OV00.04.1001; Výška_podstavy_světlíku: 0.3 m; Výška_kopule_světlíku: 0.16 m
Světlík | Půdorys 2.NP | 0.09349 | 0.34964 | SKYLIGHT |  |  | 2.2 | Světlík | MainObject | SmartPartCompressed |  |  | 2.1 |  |  |  |  |  |  |  |  | 1564Obj0798461803 | Kus | I.SV1 | NEMSOK - Kód prvku: OV00.04.1001; Výška_podstavy_světlíku: 0.3 m; Výška_kopule_světlíku: 0.16 m
Světlík | Půdorys 2.NP | 0.20149 | 0.34964 | SKYLIGHT |  |  | 2.2 | Světlík | MainObject | SmartPartCompressed |  |  | 2.1 |  |  |  |  |  |  |  |  | 1564Obj0798461788 | Kus | I.SV1 | NEMSOK - Kód prvku: OV00.04.1001; Výška_podstavy_světlíku: 0.3 m; Výška_kopule_světlíku: 0.16 m
Světlík | Půdorys 2.NP | 0.16099 | 0.34964 | SKYLIGHT |  |  | 2.2 | Světlík | MainObject | SmartPartCompressed |  |  | 2.1 |  |  |  |  |  |  |  |  | 1564Obj0798461779 | Kus | I.SV1 | NEMSOK - Kód prvku: OV00.04.1001; Výška_podstavy_světlíku: 0.3 m; Výška_kopule_světlíku: 0.16 m
Světlík | Půdorys 2.NP | 0.05299 | 0.34964 | SKYLIGHT |  |  | 2.2 | Světlík | MainObject | SmartPartCompressed |  |  | 2.1 |  |  |  |  |  |  |  |  | 1564Obj0798461264 | Kus | I.SV1 | NEMSOK - Kód prvku: OV00.04.1001; Výška_podstavy_světlíku: 0.3 m; Výška_kopule_světlíku: 0.16 m
Světlík | Půdorys 2.NP | 0.16099 | 0.34964 | SKYLIGHT |  |  | 2.2 | Světlík | MainObject | SmartPartCompressed |  |  | 2.1 |  |  |  |  |  |  |  |  | 1564Obj0798461770 | Kus | I.SV2 | NEMSOK - Kód prvku: OV00.04.1001; Výška_podstavy_světlíku: 0.3 m; Výška_kopule_světlíku: 0.16 m
Světlík | Půdorys 2.NP | 0.15664 | 0.34964 | SKYLIGHT |  |  | 2.2 | Světlík | MainObject | SmartPartCompressed |  |  | 2.1 |  |  |  |  |  |  |  |  | 1564Obj0798461753 | Kus | I.SV2 | NEMSOK - Kód prvku: OV00.04.1001; Výška_podstavy_světlíku: 0.3 m; Výška_kopule_světlíku: 0.16 m
Světlík | Půdorys 2.NP | 0.20149 | 0.34964 | SKYLIGHT |  |  | 2.2 | Světlík | MainObject | SmartPartCompressed |  |  | 2.1 |  |  |  |  |  |  |  |  | 1564Obj0798461791 | Kus | I.SV2 | NEMSOK - Kód prvku: OV00.04.1001; Výška_podstavy_světlíku: 0.3 m; Výška_kopule_světlíku: 0.16 m
Světlík | Půdorys 2.NP | 0.15664 | 0.34964 | SKYLIGHT |  |  | 2.2 | Světlík | MainObject | SmartPartCompressed |  |  | 2.1 |  |  |  |  |  |  |  |  | 1564Obj0798461794 | Kus | I.SV2 | NEMSOK - Kód prvku: OV00.04.1001; Výška_podstavy_světlíku: 0.3 m; Výška_kopule_světlíku: 0.16 m
Světlík | Půdorys 2.NP | 0.15664 | 0.34964 | SKYLIGHT |  |  | 2.2 | Světlík | MainObject | SmartPartCompressed |  |  | 2.1 |  |  |  |  |  |  |  |  | 1564Obj0798461815 | Kus | I.SV2 | NEMSOK - Kód prvku: OV00.04.1001; Výška_podstavy_světlíku: 0.3 m; Výška_kopule_světlíku: 0.16 m
Světlík | Půdorys 2.NP | 0.07144 | 0.34964 | SKYLIGHT |  |  | 2.2 | Světlík | MainObject | SmartPartCompressed |  |  | 2.1 |  |  |  |  |  |  |  |  | 1564Obj0798461834 | Kus | I.SV1 | NEMSOK - Kód prvku: OV00.04.1001; Výška_podstavy_světlíku: 0.3 m; Výška_kopule_světlíku: 0.16 m
VÝLEZ NA STŘECHU | Půdorys 2.NP | 0.11756 | 1.2 | SKYLIGHT |  |  | 2.2 | VÝLEZ NA STŘECHU | MainObject | SmartPartCompressed |  |  | 2.1 |  |  |  |  |  |  |  |  | 1564Obj0798473558 | Kus | I.VS1 | NEMSOK - Kód prvku: OV00.04.0001; Výška_podstavy_světlíku: 0.3 m; Výška_kopule_světlíku: 0.06 m
O06 | Půdorys 3.NP | 1.85 | 1.5 | WINDOW | 0 | 0 | 2.2 | O06 | MainObject | SmartPartCompressed | Izolační trojsklo 4-18-4-18-4 Ug 0,5 | 100 | 3.0 | Dřevěný rám 92 mm | Dřevěný lepený eurohranol | Bílý lak | Dřevěný lepený eurohranol | Okenní klika | není | Celoobvodové kování s pětibodovým uzávěrem | Dvojkřídlové okno otevíravé a sklápěcí, symetricky dělené s nadsvětlíkem | 1652Obj0798439626 | Kus | Okno - objekt+SmartPart | 1.9716 | 80 | 80 | 80 | 0.8 | no | 1.85 | 1.5 | 2.775
O06 | Půdorys 3.NP | 1.85 | 1.5 | WINDOW | 0 | 0 | 2.2 | O06 | MainObject | SmartPartCompressed | Izolační trojsklo 4-18-4-18-4 Ug 0,5 | 100 | 3.0 | Dřevěný rám 92 mm | Dřevěný lepený eurohranol | Bílý lak | Dřevěný lepený eurohranol | Okenní klika | není | Celoobvodové kování s pětibodovým uzávěrem | Dvojkřídlové okno otevíravé a sklápěcí, symetricky dělené s nadsvětlíkem | 1652Obj0798439587 | Kus | Okno - objekt+SmartPart | 1.9716 | 80 | 80 | 80 | 0.8 | no | 1.85 | 1.5 | 2.775
O06 | Půdorys 3.NP | 1.85 | 1.5 | WINDOW | 0 | 0 | 2.2 | O06 | MainObject | SmartPartCompressed | Izolační trojsklo 4-18-4-18-4 Ug 0,5 | 100 | 3.0 | Dřevěný rám 92 mm | Dřevěný lepený eurohranol | Bílý lak | Dřevěný lepený eurohranol | Okenní klika | není | Celoobvodové kování s pětibodovým uzávěrem | Dvojkřídlové okno otevíravé a sklápěcí, symetricky dělené s nadsvětlíkem | 1652Obj0798439546 | Kus | Okno - objekt+SmartPart | 1.9716 | 80 | 80 | 80 | 0.8 | no | 1.85 | 1.5 | 2.775
O06 | Půdorys 3.NP | 1.8 | 1.5 | WINDOW | 0 | 0 | 2.2 | O06 | MainObject | SmartPartCompressed | Izolační trojsklo 4-18-4-18-4 Ug 0,5 | 100 | 3.0 | Dřevěný rám 92 mm | Dřevěný lepený eurohranol | Bílý lak | Dřevěný lepený eurohranol | Okenní klika | není | Celoobvodové kování s pětibodovým uzávěrem | Dvojkřídlové okno otevíravé a sklápěcí, symetricky dělené s nadsvětlíkem | 1652Obj0798436309 | Kus | Okno - objekt+SmartPart | 1.9096 | 80 | 80 | 80 | 0.8 | no | 1.8 | 1.5 | 2.7
O06 | Půdorys 3.NP | 1.8 | 1.5 | WINDOW | 0 | 0 | 2.2 | O06 | MainObject | SmartPartCompressed | Izolační trojsklo 4-18-4-18-4 Ug 0,5 | 100 | 3.0 | Dřevěný rám 92 mm | Dřevěný lepený eurohranol | Bílý lak | Dřevěný lepený eurohranol | Okenní klika | není | Celoobvodové kování s pětibodovým uzávěrem | Dvojkřídlové okno otevíravé a sklápěcí, symetricky dělené s nadsvětlíkem | 1652Obj0798436349 | Kus | Okno - objekt+SmartPart | 1.9096 | 80 | 80 | 80 | 0.8 | no | 1.8 | 1.5 | 2.7
O06 | Půdorys 3.NP | 1.8 | 1.5 | WINDOW | 0 | 0 | 2.2 | O06 | MainObject | SmartPartCompressed | Izolační trojsklo 4-18-4-18-4 Ug 0,5 | 100 | 3.0 | Dřevěný rám 92 mm | Dřevěný lepený eurohranol | Bílý lak | Dřevěný lepený eurohranol | Okenní klika | není | Celoobvodové kování s pětibodovým uzávěrem | Dvojkřídlové okno otevíravé a sklápěcí, symetricky dělené s nadsvětlíkem | 1652Obj0798436362 | Kus | Okno - objekt+SmartPart | 1.9096 | 80 | 80 | 80 | 0.8 | no | 1.8 | 1.5 | 2.7
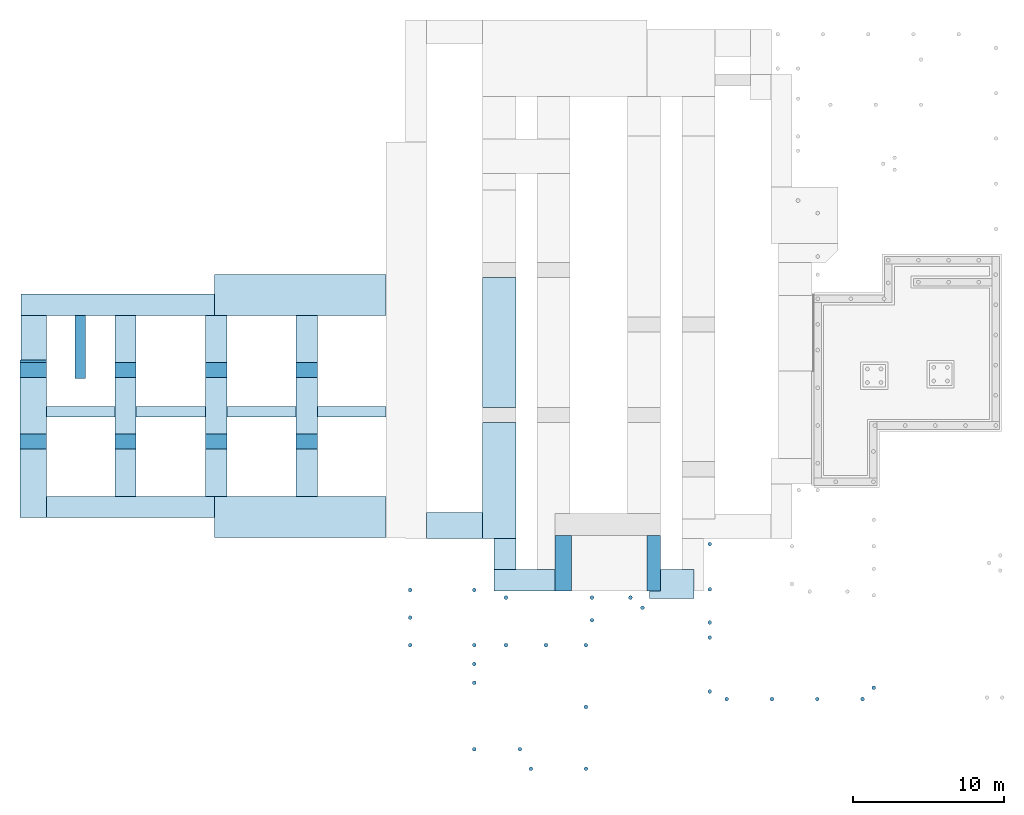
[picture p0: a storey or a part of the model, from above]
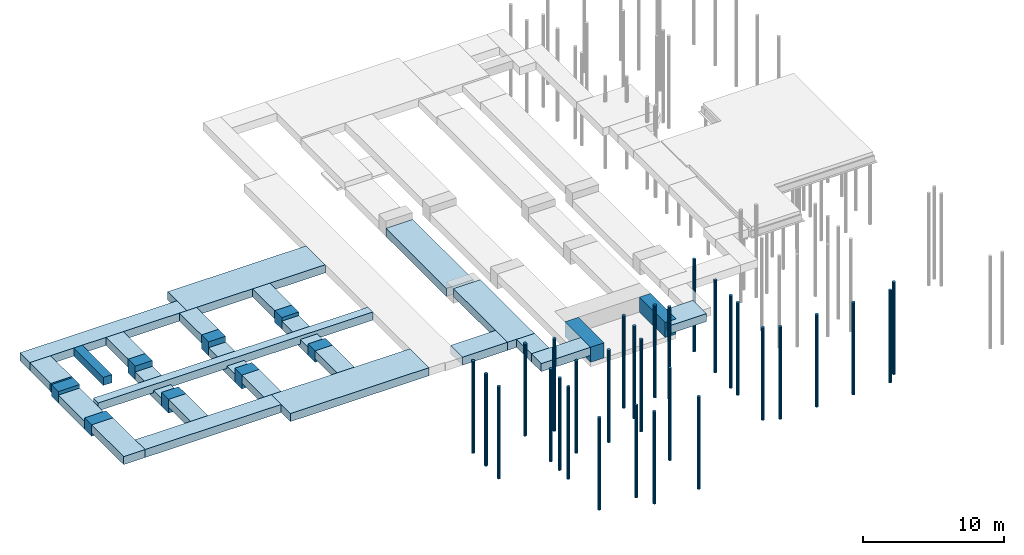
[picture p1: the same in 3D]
Properties of the parts of a building model (IFC4), part 45 of 45

# IfcWindow (265)
Name | In | OverallHeight (m) | OverallWidth (m) | PredefinedType | Dolní_hrana (m) = Horní_hrana (m) | Jednotková_cena = HeightWindowSillOutside = HeightWindowSillInside = OffsetOpeningBottom = OffsetOpeningTop = OffsetOpeningLeft = OffsetOpeningRight = Perimeter (m) | Verze programu | Označení | Plugin_Bezeichnung | Plugin_Objektname | Typ skla | Uvažované procento prosklení | Verze | Zárubeň/Rám_Typ | Zárubeň/Rám_Materiál | Zárubeň/Rám_Povrch = Křídlo_Povrch_Int. = Křídlo_Povrch_Ext. | Křídlo_Materiál | Kování_Klika_Int. | Kování_Klika_Ext. = Kování_Zámek | Kování_Závěsy | Specifikace | Allright_Stavebni_dil_ID | Jednotka | Název_objektu | GlassSurface | DeductionOpeningBottom | DeductionOpeningLeft = DeductionOpeningRight | DeductionOpeningTop | ThermalTransmittance (W/K/m2) | SmokeStop = FireExit | Height (m) | Width (m) | Area (m2)
O06 | Půdorys 3.NP | 1.8 | 1.5 | WINDOW | 0 | 0 | 2.2 | O06 | MainObject | SmartPartCompressed | Izolační trojsklo 4-18-4-18-4 Ug 0,5 | 100 | 3.0 | Dřevěný rám 92 mm | Dřevěný lepený eurohranol | Bílý lak | Dřevěný lepený eurohranol | Okenní klika | není | Celoobvodové kování s pětibodovým uzávěrem | Dvojkřídlové okno otevíravé a sklápěcí, symetricky dělené s nadsvětlíkem | 1652Obj0798439040 | Kus | Okno - objekt+SmartPart | 1.9096 | 80 | 80 | 80 | 0.8 | no | 1.8 | 1.5 | 2.7
O06 | Půdorys 3.NP | 1.8 | 1.5 | WINDOW | 0 | 0 | 2.2 | O06 | MainObject | SmartPartCompressed | Izolační trojsklo 4-18-4-18-4 Ug 0,5 | 100 | 3.0 | Dřevěný rám 92 mm | Dřevěný lepený eurohranol | Bílý lak | Dřevěný lepený eurohranol | Okenní klika | není | Celoobvodové kování s pětibodovým uzávěrem | Dvojkřídlové okno otevíravé a sklápěcí, symetricky dělené s nadsvětlíkem | 1652Obj0798439021 | Kus | Okno - objekt+SmartPart | 1.9096 | 80 | 80 | 80 | 0.8 | no | 1.8 | 1.5 | 2.7
O06 | Půdorys 3.NP | 1.8 | 1.5 | WINDOW | 0 | 0 | 2.2 | O06 | MainObject | SmartPartCompressed | Izolační trojsklo 4-18-4-18-4 Ug 0,5 | 100 | 3.0 | Dřevěný rám 92 mm | Dřevěný lepený eurohranol | Bílý lak | Dřevěný lepený eurohranol | Okenní klika | není | Celoobvodové kování s pětibodovým uzávěrem | Dvojkřídlové okno otevíravé a sklápěcí, symetricky dělené s nadsvětlíkem | 1652Obj0798439205 | Kus | Okno - objekt+SmartPart | 1.9096 | 80 | 80 | 80 | 0.8 | no | 1.8 | 1.5 | 2.7
O06 | Půdorys 3.NP | 1.8 | 1.5 | WINDOW | 0 | 0 | 2.2 | O06 | MainObject | SmartPartCompressed | Izolační trojsklo 4-18-4-18-4 Ug 0,5 | 100 | 3.0 | Dřevěný rám 92 mm | Dřevěný lepený eurohranol | Bílý lak | Dřevěný lepený eurohranol | Okenní klika | není | Celoobvodové kování s pětibodovým uzávěrem | Dvojkřídlové okno otevíravé a sklápěcí, symetricky dělené s nadsvětlíkem | 1652Obj0798439267 | Kus | Okno - objekt+SmartPart | 1.9096 | 80 | 80 | 80 | 0.8 | no | 1.8 | 1.5 | 2.7
O06 | Půdorys 3.NP | 1.8 | 1.5 | WINDOW | 0 | 0 | 2.2 | O06 | MainObject | SmartPartCompressed | Izolační trojsklo 4-18-4-18-4 Ug 0,5 | 100 | 3.0 | Dřevěný rám 92 mm | Dřevěný lepený eurohranol | Bílý lak | Dřevěný lepený eurohranol | Okenní klika | není | Celoobvodové kování s pětibodovým uzávěrem | Dvojkřídlové okno otevíravé a sklápěcí, symetricky dělené s nadsvětlíkem | 1652Obj0798439507 | Kus | Okno - objekt+SmartPart | 1.9096 | 80 | 80 | 80 | 0.8 | no | 1.8 | 1.5 | 2.7
O06 | Půdorys 3.NP | 1.8 | 1.5 | WINDOW | 0 | 0 | 2.2 | O06 | MainObject | SmartPartCompressed | Izolační trojsklo 4-18-4-18-4 Ug 0,5 | 100 | 3.0 | Dřevěný rám 92 mm | Dřevěný lepený eurohranol | Bílý lak | Dřevěný lepený eurohranol | Okenní klika | není | Celoobvodové kování s pětibodovým uzávěrem | Dvojkřídlové okno otevíravé a sklápěcí, symetricky dělené s nadsvětlíkem | 1652Obj0798439463 | Kus | Okno - objekt+SmartPart | 1.9096 | 80 | 80 | 80 | 0.8 | no | 1.8 | 1.5 | 2.7
O06 | Půdorys 3.NP | 1.8 | 1.2 | WINDOW | 0 | 0 | 2.2 | O06 | MainObject | SmartPartCompressed | Izolační trojsklo 4-18-4-18-4 Ug 0,5 | 100 | 3.0 | Dřevěný rám 92 mm | Dřevěný lepený eurohranol | Bílý lak | Dřevěný lepený eurohranol | Okenní klika | není | Celoobvodové kování s pětibodovým uzávěrem | Dvojkřídlové okno otevíravé a sklápěcí, symetricky dělené s nadsvětlíkem | 1652Obj0798436735 | Kus | Okno - objekt+SmartPart | 1.4476 | 80 | 80 | 80 | 0.8 | no | 1.8 | 1.2 | 2.16
O06 | Půdorys 3.NP | 1.8 | 1.2 | WINDOW | 0 | 0 | 2.2 | O06 | MainObject | SmartPartCompressed | Izolační trojsklo 4-18-4-18-4 Ug 0,5 | 100 | 3.0 | Dřevěný rám 92 mm | Dřevěný lepený eurohranol | Bílý lak | Dřevěný lepený eurohranol | Okenní klika | není | Celoobvodové kování s pětibodovým uzávěrem | Dvojkřídlové okno otevíravé a sklápěcí, symetricky dělené s nadsvětlíkem | 1652Obj0798436744 | Kus | Okno - objekt+SmartPart | 1.4476 | 80 | 80 | 80 | 0.8 | no | 1.8 | 1.2 | 2.16
O06 | Půdorys 3.NP | 1.8 | 1.2 | WINDOW | 0 | 0 | 2.2 | O06 | MainObject | SmartPartCompressed | Izolační trojsklo 4-18-4-18-4 Ug 0,5 | 100 | 3.0 | Dřevěný rám 92 mm | Dřevěný lepený eurohranol | Bílý lak | Dřevěný lepený eurohranol | Okenní klika | není | Celoobvodové kování s pětibodovým uzávěrem | Dvojkřídlové okno otevíravé a sklápěcí, symetricky dělené s nadsvětlíkem | 1652Obj0798436753 | Kus | Okno - objekt+SmartPart | 1.4476 | 80 | 80 | 80 | 0.8 | no | 1.8 | 1.2 | 2.16
O06 | Půdorys 3.NP | 1.8 | 1.2 | WINDOW | 0 | 0 | 2.2 | O06 | MainObject | SmartPartCompressed | Izolační trojsklo 4-18-4-18-4 Ug 0,5 | 100 | 3.0 | Dřevěný rám 92 mm | Dřevěný lepený eurohranol | Bílý lak | Dřevěný lepený eurohranol | Okenní klika | není | Celoobvodové kování s pětibodovým uzávěrem | Dvojkřídlové okno otevíravé a sklápěcí, symetricky dělené s nadsvětlíkem | 1652Obj0798436762 | Kus | Okno - objekt+SmartPart | 1.4476 | 80 | 80 | 80 | 0.8 | no | 1.8 | 1.2 | 2.16
O06 | Půdorys 3.NP | 1.8 | 1.5 | WINDOW | 0 | 0 | 2.2 | O06 | MainObject | SmartPartCompressed | Izolační trojsklo 4-18-4-18-4 Ug 0,5 | 100 | 3.0 | Dřevěný rám 92 mm | Dřevěný lepený eurohranol | Bílý lak | Dřevěný lepený eurohranol | Okenní klika | není | Celoobvodové kování s pětibodovým uzávěrem | Dvojkřídlové okno otevíravé a sklápěcí, symetricky dělené s nadsvětlíkem | 1652Obj0798436650 | Kus | Okno - objekt+SmartPart | 1.9096 | 80 | 80 | 80 | 0.8 | no | 1.8 | 1.5 | 2.7
O06 | Půdorys 3.NP | 1.8 | 1.5 | WINDOW | 0 | 0 | 2.2 | O06 | MainObject | SmartPartCompressed | Izolační trojsklo 4-18-4-18-4 Ug 0,5 | 100 | 3.0 | Dřevěný rám 92 mm | Dřevěný lepený eurohranol | Bílý lak | Dřevěný lepený eurohranol | Okenní klika | není | Celoobvodové kování s pětibodovým uzávěrem | Dvojkřídlové okno otevíravé a sklápěcí, symetricky dělené s nadsvětlíkem | 1652Obj0798436659 | Kus | Okno - objekt+SmartPart | 1.9096 | 80 | 80 | 80 | 0.8 | no | 1.8 | 1.5 | 2.7
O06 | Půdorys 3.NP | 1.8 | 1.5 | WINDOW | 0 | 0 | 2.2 | O06 | MainObject | SmartPartCompressed | Izolační trojsklo 4-18-4-18-4 Ug 0,5 | 100 | 3.0 | Dřevěný rám 92 mm | Dřevěný lepený eurohranol | Bílý lak | Dřevěný lepený eurohranol | Okenní klika | není | Celoobvodové kování s pětibodovým uzávěrem | Dvojkřídlové okno otevíravé a sklápěcí, symetricky dělené s nadsvětlíkem | 1652Obj0798436668 | Kus | Okno - objekt+SmartPart | 1.9096 | 80 | 80 | 80 | 0.8 | no | 1.8 | 1.5 | 2.7
O06 | Půdorys 3.NP | 1.8 | 1.5 | WINDOW | 0 | 0 | 2.2 | O06 | MainObject | SmartPartCompressed | Izolační trojsklo 4-18-4-18-4 Ug 0,5 | 100 | 3.0 | Dřevěný rám 92 mm | Dřevěný lepený eurohranol | Bílý lak | Dřevěný lepený eurohranol | Okenní klika | není | Celoobvodové kování s pětibodovým uzávěrem | Dvojkřídlové okno otevíravé a sklápěcí, symetricky dělené s nadsvětlíkem | 1652Obj0798436677 | Kus | Okno - objekt+SmartPart | 1.9096 | 80 | 80 | 80 | 0.8 | no | 1.8 | 1.5 | 2.7
O06 | Půdorys 3.NP | 1.8 | 1.5 | WINDOW | 0 | 0 | 2.2 | O06 | MainObject | SmartPartCompressed | Izolační trojsklo 4-18-4-18-4 Ug 0,5 | 100 | 3.0 | Dřevěný rám 92 mm | Dřevěný lepený eurohranol | Bílý lak | Dřevěný lepený eurohranol | Okenní klika | není | Celoobvodové kování s pětibodovým uzávěrem | Dvojkřídlové okno otevíravé a sklápěcí, symetricky dělené s nadsvětlíkem | 1652Obj0798436686 | Kus | Okno - objekt+SmartPart | 1.9096 | 80 | 80 | 80 | 0.8 | no | 1.8 | 1.5 | 2.7
O06 | Půdorys 3.NP | 1.8 | 1.5 | WINDOW | 0 | 0 | 2.2 | O06 | MainObject | SmartPartCompressed | Izolační trojsklo 4-18-4-18-4 Ug 0,5 | 100 | 3.0 | Dřevěný rám 92 mm | Dřevěný lepený eurohranol | Bílý lak | Dřevěný lepený eurohranol | Okenní klika | není | Celoobvodové kování s pětibodovým uzávěrem | Dvojkřídlové okno otevíravé a sklápěcí, symetricky dělené s nadsvětlíkem | 1652Obj0798436606 | Kus | Okno - objekt+SmartPart | 1.9096 | 80 | 80 | 80 | 0.8 | no | 1.8 | 1.5 | 2.7
O06 | Půdorys 3.NP | 1.8 | 1.2 | WINDOW | 0 | 0 | 2.2 | O06 | MainObject | SmartPartCompressed | Izolační trojsklo 4-18-4-18-4 Ug 0,5 | 100 | 3.0 | Dřevěný rám 92 mm | Dřevěný lepený eurohranol | Bílý lak | Dřevěný lepený eurohranol | Okenní klika | není | Celoobvodové kování s pětibodovým uzávěrem | Dvojkřídlové okno otevíravé a sklápěcí, symetricky dělené s nadsvětlíkem | 1652Obj0798436490 | Kus | Okno - objekt+SmartPart | 1.4476 | 80 | 80 | 80 | 0.8 | no | 1.8 | 1.2 | 2.16
O06 | Půdorys 3.NP | 1.8 | 1.2 | WINDOW | 0 | 0 | 2.2 | O06 | MainObject | SmartPartCompressed | Izolační trojsklo 4-18-4-18-4 Ug 0,5 | 100 | 3.0 | Dřevěný rám 92 mm | Dřevěný lepený eurohranol | Bílý lak | Dřevěný lepený eurohranol | Okenní klika | není | Celoobvodové kování s pětibodovým uzávěrem | Dvojkřídlové okno otevíravé a sklápěcí, symetricky dělené s nadsvětlíkem | 1652Obj0798436499 | Kus | Okno - objekt+SmartPart | 1.4476 | 80 | 80 | 80 | 0.8 | no | 1.8 | 1.2 | 2.16
O06 | Půdorys 3.NP | 1.8 | 1.2 | WINDOW | 0 | 0 | 2.2 | O06 | MainObject | SmartPartCompressed | Izolační trojsklo 4-18-4-18-4 Ug 0,5 | 100 | 3.0 | Dřevěný rám 92 mm | Dřevěný lepený eurohranol | Bílý lak | Dřevěný lepený eurohranol | Okenní klika | není | Celoobvodové kování s pětibodovým uzávěrem | Dvojkřídlové okno otevíravé a sklápěcí, symetricky dělené s nadsvětlíkem | 1652Obj0798436508 | Kus | Okno - objekt+SmartPart | 1.4476 | 80 | 80 | 80 | 0.8 | no | 1.8 | 1.2 | 2.16
O06 | Půdorys 3.NP | 1.8 | 1.2 | WINDOW | 0 | 0 | 2.2 | O06 | MainObject | SmartPartCompressed | Izolační trojsklo 4-18-4-18-4 Ug 0,5 | 100 | 3.0 | Dřevěný rám 92 mm | Dřevěný lepený eurohranol | Bílý lak | Dřevěný lepený eurohranol | Okenní klika | není | Celoobvodové kování s pětibodovým uzávěrem | Dvojkřídlové okno otevíravé a sklápěcí, symetricky dělené s nadsvětlíkem | 1652Obj0798436446 | Kus | Okno - objekt+SmartPart | 1.4476 | 80 | 80 | 80 | 0.8 | no | 1.8 | 1.2 | 2.16
O01 | Půdorys 3.NP | 1.2 | 0.6 | WINDOW | 0 | 0 | 2.2 | O01 | MainObject | SmartPartCompressed |  | 100 | 3.0 | Dřevěný rám 92 mm | Dřevěný lepený eurohranol | Bílý lak | Dřevěný lepený eurohranol | Okenní klika | není | Celoobvodové kování s pětibodovým uzávěrem |  | 1652Obj0798442799 | Kus | Okno - objekt+SmartPart | 0 | 20 | 20 | 20 | 0.8 | no | 1.2 | 0.6 | 0.72
Parapet vnější | Půdorys 3.NP | 0.005 | 1.46 | WINDOW |  |  |  | Parapet vnější |  |  |  |  |  |  |  |  |  |  |  |  |  | 1652Obj0798443508 | m | Parapet - objekt+SmartPart | Material: PLECH; NEMSOK - Absolutní_výška: 0.03 m; Práce: Klempířské práce; Tloušťka: 0.2 m; Výška: 0.005 m; Objem: 0.0019475; Plocha: 0.36; Poloha (vnitřní/venkovní): 1; Materiál: PLECH
Parapet vnější | Půdorys 3.NP | 0.005 | 1.42 | WINDOW |  |  |  | Parapet vnější |  |  |  |  |  |  |  |  |  |  |  |  |  | 1652Obj0798444226 | m | Parapet - objekt+SmartPart | Material: PLECH; NEMSOK - Absolutní_výška: 0.03 m; Práce: Klempířské práce; Tloušťka: 0.2 m; Výška: 0.005 m; Objem: 0.0018945; Plocha: 0.3504; Poloha (vnitřní/venkovní): 1; Materiál: PLECH
O06 | Půdorys 3.NP | 3.35 | 1.875 | WINDOW | 0 | 0 | 2.2 | O06 | MainObject | SmartPartCompressed | Izolační trojsklo 4-18-4-18-4 Ug 0,5 | 100 | 3.0 | Dřevěný rám 92 mm | Dřevěný lepený eurohranol | Bílý lak | Dřevěný lepený eurohranol | Okenní klika | není | Celoobvodové kování s pětibodovým uzávěrem | Dvojkřídlové okno otevíravé a sklápěcí, symetricky dělené s nadsvětlíkem | 1652Obj0798446246 | Kus | Okno - objekt+SmartPart | 0.357 | 60 | 60 | 60 | 0.8 | no | 3.35 | 1.875 | 6.281
O01 | Půdorys 3.NP | 1.45 | 2.4 | WINDOW | 0 | 0 | 2.2 | O01 | MainObject | SmartPartCompressed | Izolační trojsklo 4-18-4-18-4 Ug 0,5 | 100 | 3.0 | Dřevěný rám 92 mm | Dřevěný lepený eurohranol | Bílý lak | Dřevěný lepený eurohranol | Okenní klika | není | Celoobvodové kování s pětibodovým uzávěrem | Jednokřídlové okno otevíravé a sklápěcí | 1652Obj0798418541 | Kus | Okno - objekt+SmartPart | 2.814 | 25 | 100 | 25 | 0.8 | no | 1.45 | 2.4 | 3.48
O06 | Půdorys 4.NP | 1.85 | 1.5 | WINDOW | 0 | 0 | 2.2 | O06 | MainObject | SmartPartCompressed | Izolační trojsklo 4-18-4-18-4 Ug 0,5 | 100 | 3.0 | Dřevěný rám 92 mm | Dřevěný lepený eurohranol | Bílý lak | Dřevěný lepený eurohranol | Okenní klika | není | Celoobvodové kování s pětibodovým uzávěrem | Dvojkřídlové okno otevíravé a sklápěcí, symetricky dělené s nadsvětlíkem | 1752Obj0000018012 | Kus | Okno - objekt+SmartPart | 1.9716 | 80 | 80 | 80 | 0.8 | no | 1.85 | 1.5 | 2.775
O06 | Půdorys 4.NP | 1.85 | 1.5 | WINDOW | 0 | 0 | 2.2 | O06 | MainObject | SmartPartCompressed | Izolační trojsklo 4-18-4-18-4 Ug 0,5 | 100 | 3.0 | Dřevěný rám 92 mm | Dřevěný lepený eurohranol | Bílý lak | Dřevěný lepený eurohranol | Okenní klika | není | Celoobvodové kování s pětibodovým uzávěrem | Dvojkřídlové okno otevíravé a sklápěcí, symetricky dělené s nadsvětlíkem | 1752Obj0000017944 | Kus | Okno - objekt+SmartPart | 1.9716 | 80 | 80 | 80 | 0.8 | no | 1.85 | 1.5 | 2.775
O06 | Půdorys 4.NP | 1.85 | 1.5 | WINDOW | 0 | 0 | 2.2 | O06 | MainObject | SmartPartCompressed | Izolační trojsklo 4-18-4-18-4 Ug 0,5 | 100 | 3.0 | Dřevěný rám 92 mm | Dřevěný lepený eurohranol | Bílý lak | Dřevěný lepený eurohranol | Okenní klika | není | Celoobvodové kování s pětibodovým uzávěrem | Dvojkřídlové okno otevíravé a sklápěcí, symetricky dělené s nadsvětlíkem | 1752Obj0000018080 | Kus | Okno - objekt+SmartPart | 1.9716 | 80 | 80 | 80 | 0.8 | no | 1.85 | 1.5 | 2.775
O06 | Půdorys 4.NP | 1.8 | 1.5 | WINDOW | 0 | 0 | 2.2 | O06 | MainObject | SmartPartCompressed | Izolační trojsklo 4-18-4-18-4 Ug 0,5 | 100 | 3.0 | Dřevěný rám 92 mm | Dřevěný lepený eurohranol | Bílý lak | Dřevěný lepený eurohranol | Okenní klika | není | Celoobvodové kování s pětibodovým uzávěrem | Dvojkřídlové okno otevíravé a sklápěcí, symetricky dělené s nadsvětlíkem | 1752Obj0000018223 | Kus | Okno - objekt+SmartPart | 1.9096 | 80 | 80 | 80 | 0.8 | no | 1.8 | 1.5 | 2.7
O06 | Půdorys 4.NP | 1.8 | 1.5 | WINDOW | 0 | 0 | 2.2 | O06 | MainObject | SmartPartCompressed | Izolační trojsklo 4-18-4-18-4 Ug 0,5 | 100 | 3.0 | Dřevěný rám 92 mm | Dřevěný lepený eurohranol | Bílý lak | Dřevěný lepený eurohranol | Okenní klika | není | Celoobvodové kování s pětibodovým uzávěrem | Dvojkřídlové okno otevíravé a sklápěcí, symetricky dělené s nadsvětlíkem | 1752Obj0000018225 | Kus | Okno - objekt+SmartPart | 1.9096 | 80 | 80 | 80 | 0.8 | no | 1.8 | 1.5 | 2.7
O06 | Půdorys 4.NP | 1.8 | 1.5 | WINDOW | 0 | 0 | 2.2 | O06 | MainObject | SmartPartCompressed | Izolační trojsklo 4-18-4-18-4 Ug 0,5 | 100 | 3.0 | Dřevěný rám 92 mm | Dřevěný lepený eurohranol | Bílý lak | Dřevěný lepený eurohranol | Okenní klika | není | Celoobvodové kování s pětibodovým uzávěrem | Dvojkřídlové okno otevíravé a sklápěcí, symetricky dělené s nadsvětlíkem | 1752Obj0000018084 | Kus | Okno - objekt+SmartPart | 1.9096 | 80 | 80 | 80 | 0.8 | no | 1.8 | 1.5 | 2.7
O06 | Půdorys 4.NP | 1.8 | 1.5 | WINDOW | 0 | 0 | 2.2 | O06 | MainObject | SmartPartCompressed | Izolační trojsklo 4-18-4-18-4 Ug 0,5 | 100 | 3.0 | Dřevěný rám 92 mm | Dřevěný lepený eurohranol | Bílý lak | Dřevěný lepený eurohranol | Okenní klika | není | Celoobvodové kování s pětibodovým uzávěrem | Dvojkřídlové okno otevíravé a sklápěcí, symetricky dělené s nadsvětlíkem | 1752Obj0000018150 | Kus | Okno - objekt+SmartPart | 1.9096 | 80 | 80 | 80 | 0.8 | no | 1.8 | 1.5 | 2.7
O06 | Půdorys 4.NP | 1.8 | 1.5 | WINDOW | 0 | 0 | 2.2 | O06 | MainObject | SmartPartCompressed | Izolační trojsklo 4-18-4-18-4 Ug 0,5 | 100 | 3.0 | Dřevěný rám 92 mm | Dřevěný lepený eurohranol | Bílý lak | Dřevěný lepený eurohranol | Okenní klika | není | Celoobvodové kování s pětibodovým uzávěrem | Dvojkřídlové okno otevíravé a sklápěcí, symetricky dělené s nadsvětlíkem | 1752Obj0000018218 | Kus | Okno - objekt+SmartPart | 1.9096 | 80 | 80 | 80 | 0.8 | no | 1.8 | 1.5 | 2.7
O06 | Půdorys 4.NP | 1.8 | 1.5 | WINDOW | 0 | 0 | 2.2 | O06 | MainObject | SmartPartCompressed | Izolační trojsklo 4-18-4-18-4 Ug 0,5 | 100 | 3.0 | Dřevěný rám 92 mm | Dřevěný lepený eurohranol | Bílý lak | Dřevěný lepený eurohranol | Okenní klika | není | Celoobvodové kování s pětibodovým uzávěrem | Dvojkřídlové okno otevíravé a sklápěcí, symetricky dělené s nadsvětlíkem | 1752Obj0000018220 | Kus | Okno - objekt+SmartPart | 1.9096 | 80 | 80 | 80 | 0.8 | no | 1.8 | 1.5 | 2.7
O06 | Půdorys 4.NP | 1.8 | 1.5 | WINDOW | 0 | 0 | 2.2 | O06 | MainObject | SmartPartCompressed | Izolační trojsklo 4-18-4-18-4 Ug 0,5 | 100 | 3.0 | Dřevěný rám 92 mm | Dřevěný lepený eurohranol | Bílý lak | Dřevěný lepený eurohranol | Okenní klika | není | Celoobvodové kování s pětibodovým uzávěrem | Dvojkřídlové okno otevíravé a sklápěcí, symetricky dělené s nadsvětlíkem | 1752Obj0798426287 | Kus | Okno - objekt+SmartPart | 1.9096 | 80 | 80 | 80 | 0.8 | no | 1.8 | 1.5 | 2.7
O06 | Půdorys 4.NP | 1.8 | 1.5 | WINDOW | 0 | 0 | 2.2 | O06 | MainObject | SmartPartCompressed | Izolační trojsklo 4-18-4-18-4 Ug 0,5 | 100 | 3.0 | Dřevěný rám 92 mm | Dřevěný lepený eurohranol | Bílý lak | Dřevěný lepený eurohranol | Okenní klika | není | Celoobvodové kování s pětibodovým uzávěrem | Dvojkřídlové okno otevíravé a sklápěcí, symetricky dělené s nadsvětlíkem | 1752Obj0000016420 | Kus | Okno - objekt+SmartPart | 1.9096 | 80 | 80 | 80 | 0.8 | no | 1.8 | 1.5 | 2.7
O06 | Půdorys 4.NP | 1.8 | 1.5 | WINDOW | 0 | 0 | 2.2 | O06 | MainObject | SmartPartCompressed | Izolační trojsklo 4-18-4-18-4 Ug 0,5 | 100 | 3.0 | Dřevěný rám 92 mm | Dřevěný lepený eurohranol | Bílý lak | Dřevěný lepený eurohranol | Okenní klika | není | Celoobvodové kování s pětibodovým uzávěrem | Dvojkřídlové okno otevíravé a sklápěcí, symetricky dělené s nadsvětlíkem | 1752Obj0000016381 | Kus | Okno - objekt+SmartPart | 1.9096 | 80 | 80 | 80 | 0.8 | no | 1.8 | 1.5 | 2.7
O01 | Půdorys 4.NP | 1.2 | 0.6 | WINDOW | 0 | 0 | 2.2 | O01 | MainObject | SmartPartCompressed |  | 100 | 3.0 | Dřevěný rám 92 mm | Dřevěný lepený eurohranol | Bílý lak | Dřevěný lepený eurohranol | Okenní klika | není | Celoobvodové kování s pětibodovým uzávěrem |  | 1752Obj0798429067 | Kus | Okno - objekt+SmartPart | 0 | 20 | 20 | 20 | 0.8 | no | 1.2 | 0.6 | 0.72
O06 | Půdorys 4.NP | 1.8 | 1.5 | WINDOW | 0 | 0 | 2.2 | O06 | MainObject | SmartPartCompressed | Izolační trojsklo 4-18-4-18-4 Ug 0,5 | 100 | 3.0 | Dřevěný rám 92 mm | Dřevěný lepený eurohranol | Bílý lak | Dřevěný lepený eurohranol | Okenní klika | není | Celoobvodové kování s pětibodovým uzávěrem | Dvojkřídlové okno otevíravé a sklápěcí, symetricky dělené s nadsvětlíkem | 1752Obj0798429947 | Kus | Okno - objekt+SmartPart | 1.6864 | 80 | 80 | 80 | 0.8 | no | 1.8 | 1.5 | 2.7
O06 | Půdorys 4.NP | 1.5 | 1.5 | WINDOW | 0 | 0 | 2.2 | O06 | MainObject | SmartPartCompressed | Izolační trojsklo 4-18-4-18-4 Ug 0,5 | 100 | 3.0 | Dřevěný rám 92 mm | Dřevěný lepený eurohranol | Bílý lak | Dřevěný lepený eurohranol | Okenní klika | není | Celoobvodové kování s pětibodovým uzávěrem | Dvojkřídlové okno otevíravé a sklápěcí, symetricky dělené s nadsvětlíkem | 1752Obj0798426352 | Kus | Okno - objekt+SmartPart | 1.5376 | 80 | 80 | 80 | 0.8 | no | 1.5 | 1.5 | 2.25
O01 | Půdorys 4.NP | 0.85 | 2.4 | WINDOW | 0 | 0 | 2.2 | O01 | MainObject | SmartPartCompressed | Izolační trojsklo 4-18-4-18-4 Ug 0,5 | 100 | 3.0 | Dřevěný rám 92 mm | Dřevěný lepený eurohranol | Bílý lak | Dřevěný lepený eurohranol | Okenní klika | není | Celoobvodové kování s pětibodovým uzávěrem | Jednokřídlové okno otevíravé a sklápěcí | 1752Obj0000004761 | Kus | Okno - objekt+SmartPart | 1.218 | 50 | 100 | 200 | 0.8 | no | 0.85 | 2.4 | 2.04
O01 | Půdorys 4.NP | 1.4 | 2.4 | WINDOW | 0 | 0 | 2.2 | O01 | MainObject | SmartPartCompressed | Izolační trojsklo 4-18-4-18-4 Ug 0,5 | 100 | 3.0 | Dřevěný rám 92 mm | Dřevěný lepený eurohranol | Bílý lak | Dřevěný lepený eurohranol | Okenní klika | není | Celoobvodové kování s pětibodovým uzávěrem | Jednokřídlové okno otevíravé a sklápěcí | 1752Obj0000004759 | Kus | Okno - objekt+SmartPart | 2.2344 | 80 | 80 | 80 | 0.8 | no | 1.4 | 2.4 | 3.36
O06 | Půdorys 4.NP | 1.45 | 1.875 | WINDOW | 0 | 0 | 2.2 | O06 | MainObject | SmartPartCompressed | Izolační trojsklo 4-18-4-18-4 Ug 0,5 | 100 | 3.0 | Dřevěný rám 92 mm | Dřevěný lepený eurohranol | Bílý lak | Dřevěný lepený eurohranol | Okenní klika | není | Celoobvodové kování s pětibodovým uzávěrem | Dvojkřídlové okno otevíravé a sklápěcí, symetricky dělené s nadsvětlíkem | 1752Obj0798428004 | Kus | Okno - objekt+SmartPart | 0 | 60 | 60 | 60 | 0.8 | no | 1.45 | 1.875 | 2.719
O06 | Půdorys 4.NP | 1.8 | 1.2 | WINDOW | 0 | 0 | 2.2 | O06 | MainObject | SmartPartCompressed | Izolační trojsklo 4-18-4-18-4 Ug 0,5 | 100 | 3.0 | Dřevěný rám 92 mm | Dřevěný lepený eurohranol | Bílý lak | Dřevěný lepený eurohranol | Okenní klika | není | Celoobvodové kování s pětibodovým uzávěrem | Dvojkřídlové okno otevíravé a sklápěcí, symetricky dělené s nadsvětlíkem | 1752Obj0000015828 | Kus | Okno - objekt+SmartPart | 1.4476 | 80 | 80 | 80 | 0.8 | no | 1.8 | 1.2 | 2.16
O06 | Půdorys 4.NP | 1.8 | 1.2 | WINDOW | 0 | 0 | 2.2 | O06 | MainObject | SmartPartCompressed | Izolační trojsklo 4-18-4-18-4 Ug 0,5 | 100 | 3.0 | Dřevěný rám 92 mm | Dřevěný lepený eurohranol | Bílý lak | Dřevěný lepený eurohranol | Okenní klika | není | Celoobvodové kování s pětibodovým uzávěrem | Dvojkřídlové okno otevíravé a sklápěcí, symetricky dělené s nadsvětlíkem | 1752Obj0000015820 | Kus | Okno - objekt+SmartPart | 1.4476 | 80 | 80 | 80 | 0.8 | no | 1.8 | 1.2 | 2.16
O06 | Půdorys 4.NP | 1.8 | 1.2 | WINDOW | 0 | 0 | 2.2 | O06 | MainObject | SmartPartCompressed | Izolační trojsklo 4-18-4-18-4 Ug 0,5 | 100 | 3.0 | Dřevěný rám 92 mm | Dřevěný lepený eurohranol | Bílý lak | Dřevěný lepený eurohranol | Okenní klika | není | Celoobvodové kování s pětibodovým uzávěrem | Dvojkřídlové okno otevíravé a sklápěcí, symetricky dělené s nadsvětlíkem | 1752Obj0000015812 | Kus | Okno - objekt+SmartPart | 1.4476 | 80 | 80 | 80 | 0.8 | no | 1.8 | 1.2 | 2.16
O06 | Půdorys 4.NP | 1.8 | 1.2 | WINDOW | 0 | 0 | 2.2 | O06 | MainObject | SmartPartCompressed | Izolační trojsklo 4-18-4-18-4 Ug 0,5 | 100 | 3.0 | Dřevěný rám 92 mm | Dřevěný lepený eurohranol | Bílý lak | Dřevěný lepený eurohranol | Okenní klika | není | Celoobvodové kování s pětibodovým uzávěrem | Dvojkřídlové okno otevíravé a sklápěcí, symetricky dělené s nadsvětlíkem | 1752Obj0000015773 | Kus | Okno - objekt+SmartPart | 1.4476 | 80 | 80 | 80 | 0.8 | no | 1.8 | 1.2 | 2.16
O06 | Půdorys 4.NP | 1.8 | 1.5 | WINDOW | 0 | 0 | 2.2 | O06 | MainObject | SmartPartCompressed | Izolační trojsklo 4-18-4-18-4 Ug 0,5 | 100 | 3.0 | Dřevěný rám 92 mm | Dřevěný lepený eurohranol | Bílý lak | Dřevěný lepený eurohranol | Okenní klika | není | Celoobvodové kování s pětibodovým uzávěrem | Dvojkřídlové okno otevíravé a sklápěcí, symetricky dělené s nadsvětlíkem | 1752Obj0000015765 | Kus | Okno - objekt+SmartPart | 1.9096 | 80 | 80 | 80 | 0.8 | no | 1.8 | 1.5 | 2.7
O06 | Půdorys 4.NP | 1.8 | 1.5 | WINDOW | 0 | 0 | 2.2 | O06 | MainObject | SmartPartCompressed | Izolační trojsklo 4-18-4-18-4 Ug 0,5 | 100 | 3.0 | Dřevěný rám 92 mm | Dřevěný lepený eurohranol | Bílý lak | Dřevěný lepený eurohranol | Okenní klika | není | Celoobvodové kování s pětibodovým uzávěrem | Dvojkřídlové okno otevíravé a sklápěcí, symetricky dělené s nadsvětlíkem | 1752Obj0000015757 | Kus | Okno - objekt+SmartPart | 1.9096 | 80 | 80 | 80 | 0.8 | no | 1.8 | 1.5 | 2.7
O06 | Půdorys 4.NP | 1.8 | 1.5 | WINDOW | 0 | 0 | 2.2 | O06 | MainObject | SmartPartCompressed | Izolační trojsklo 4-18-4-18-4 Ug 0,5 | 100 | 3.0 | Dřevěný rám 92 mm | Dřevěný lepený eurohranol | Bílý lak | Dřevěný lepený eurohranol | Okenní klika | není | Celoobvodové kování s pětibodovým uzávěrem | Dvojkřídlové okno otevíravé a sklápěcí, symetricky dělené s nadsvětlíkem | 1752Obj0000015749 | Kus | Okno - objekt+SmartPart | 1.9096 | 80 | 80 | 80 | 0.8 | no | 1.8 | 1.5 | 2.7
O06 | Půdorys 4.NP | 1.8 | 1.5 | WINDOW | 0 | 0 | 2.2 | O06 | MainObject | SmartPartCompressed | Izolační trojsklo 4-18-4-18-4 Ug 0,5 | 100 | 3.0 | Dřevěný rám 92 mm | Dřevěný lepený eurohranol | Bílý lak | Dřevěný lepený eurohranol | Okenní klika | není | Celoobvodové kování s pětibodovým uzávěrem | Dvojkřídlové okno otevíravé a sklápěcí, symetricky dělené s nadsvětlíkem | 1752Obj0000015694 | Kus | Okno - objekt+SmartPart | 1.9096 | 80 | 80 | 80 | 0.8 | no | 1.8 | 1.5 | 2.7
O06 | Půdorys 4.NP | 1.8 | 1.5 | WINDOW | 0 | 0 | 2.2 | O06 | MainObject | SmartPartCompressed | Izolační trojsklo 4-18-4-18-4 Ug 0,5 | 100 | 3.0 | Dřevěný rám 92 mm | Dřevěný lepený eurohranol | Bílý lak | Dřevěný lepený eurohranol | Okenní klika | není | Celoobvodové kování s pětibodovým uzávěrem | Dvojkřídlové okno otevíravé a sklápěcí, symetricky dělené s nadsvětlíkem | 1752Obj0000015733 | Kus | Okno - objekt+SmartPart | 1.9096 | 80 | 80 | 80 | 0.8 | no | 1.8 | 1.5 | 2.7
O06 | Půdorys 4.NP | 1.8 | 1.5 | WINDOW | 0 | 0 | 2.2 | O06 | MainObject | SmartPartCompressed | Izolační trojsklo 4-18-4-18-4 Ug 0,5 | 100 | 3.0 | Dřevěný rám 92 mm | Dřevěný lepený eurohranol | Bílý lak | Dřevěný lepený eurohranol | Okenní klika | není | Celoobvodové kování s pětibodovým uzávěrem | Dvojkřídlové okno otevíravé a sklápěcí, symetricky dělené s nadsvětlíkem | 1752Obj0000015741 | Kus | Okno - objekt+SmartPart | 1.9096 | 80 | 80 | 80 | 0.8 | no | 1.8 | 1.5 | 2.7
O06 | Půdorys 4.NP | 1.8 | 1.2 | WINDOW | 0 | 0 | 2.2 | O06 | MainObject | SmartPartCompressed | Izolační trojsklo 4-18-4-18-4 Ug 0,5 | 100 | 3.0 | Dřevěný rám 92 mm | Dřevěný lepený eurohranol | Bílý lak | Dřevěný lepený eurohranol | Okenní klika | není | Celoobvodové kování s pětibodovým uzávěrem | Dvojkřídlové okno otevíravé a sklápěcí, symetricky dělené s nadsvětlíkem | 1752Obj0000015852 | Kus | Okno - objekt+SmartPart | 1.4476 | 80 | 80 | 80 | 0.8 | no | 1.8 | 1.2 | 2.16
O06 | Půdorys 4.NP | 1.8 | 1.2 | WINDOW | 0 | 0 | 2.2 | O06 | MainObject | SmartPartCompressed | Izolační trojsklo 4-18-4-18-4 Ug 0,5 | 100 | 3.0 | Dřevěný rám 92 mm | Dřevěný lepený eurohranol | Bílý lak | Dřevěný lepený eurohranol | Okenní klika | není | Celoobvodové kování s pětibodovým uzávěrem | Dvojkřídlové okno otevíravé a sklápěcí, symetricky dělené s nadsvětlíkem | 1752Obj0000015844 | Kus | Okno - objekt+SmartPart | 1.4476 | 80 | 80 | 80 | 0.8 | no | 1.8 | 1.2 | 2.16
O06 | Půdorys 4.NP | 1.8 | 1.2 | WINDOW | 0 | 0 | 2.2 | O06 | MainObject | SmartPartCompressed | Izolační trojsklo 4-18-4-18-4 Ug 0,5 | 100 | 3.0 | Dřevěný rám 92 mm | Dřevěný lepený eurohranol | Bílý lak | Dřevěný lepený eurohranol | Okenní klika | není | Celoobvodové kování s pětibodovým uzávěrem | Dvojkřídlové okno otevíravé a sklápěcí, symetricky dělené s nadsvětlíkem | 1752Obj0000015836 | Kus | Okno - objekt+SmartPart | 1.4476 | 80 | 80 | 80 | 0.8 | no | 1.8 | 1.2 | 2.16
O06 | Půdorys 4.NP | 1.8 | 1.2 | WINDOW | 0 | 0 | 2.2 | O06 | MainObject | SmartPartCompressed | Izolační trojsklo 4-18-4-18-4 Ug 0,5 | 100 | 3.0 | Dřevěný rám 92 mm | Dřevěný lepený eurohranol | Bílý lak | Dřevěný lepený eurohranol | Okenní klika | není | Celoobvodové kování s pětibodovým uzávěrem | Dvojkřídlové okno otevíravé a sklápěcí, symetricky dělené s nadsvětlíkem | 1752Obj0000015860 | Kus | Okno - objekt+SmartPart | 1.4476 | 80 | 80 | 80 | 0.8 | no | 1.8 | 1.2 | 2.16
O06 | Půdorys 5.NP | 1.5 | 0.9 | WINDOW | 0 | 0 | 2.2 | O06 | MainObject | SmartPartCompressed | Izolační trojsklo 4-18-4-18-4 Ug 0,5 | 100 | 3.0 | Dřevěný rám 92 mm | Dřevěný lepený eurohranol | Bílý lak | Dřevěný lepený eurohranol | Okenní klika | není | Celoobvodové kování s pětibodovým uzávěrem | Dvojkřídlové okno otevíravé a sklápěcí, symetricky dělené s nadsvětlíkem | 1852Obj0798433062 | Kus | Okno - objekt+SmartPart | 0.7936 | 80 | 80 | 80 | 0.8 | no | 1.5 | 0.9 | 1.35
O06 | Půdorys 5.NP | 1.5 | 0.9 | WINDOW | 0 | 0 | 2.2 | O06 | MainObject | SmartPartCompressed | Izolační trojsklo 4-18-4-18-4 Ug 0,5 | 100 | 3.0 | Dřevěný rám 92 mm | Dřevěný lepený eurohranol | Bílý lak | Dřevěný lepený eurohranol | Okenní klika | není | Celoobvodové kování s pětibodovým uzávěrem | Dvojkřídlové okno otevíravé a sklápěcí, symetricky dělené s nadsvětlíkem | 1852Obj0798426650 | Kus | Okno - objekt+SmartPart | 0.7936 | 80 | 80 | 80 | 0.8 | no | 1.5 | 0.9 | 1.35
O06 | Půdorys 5.NP | 0.9 | 0.9 | WINDOW | 0 | 0 | 2.2 | O06 | MainObject | SmartPartCompressed | Izolační trojsklo 4-18-4-18-4 Ug 0,5 | 100 | 3.0 | Dřevěný rám 92 mm | Dřevěný lepený eurohranol | Bílý lak | Dřevěný lepený eurohranol | Okenní klika | není | Celoobvodové kování s pětibodovým uzávěrem | Dvojkřídlové okno otevíravé a sklápěcí, symetricky dělené s nadsvětlíkem | 1852Obj0798426739 | Kus | Okno - objekt+SmartPart | 0.4096 | 80 | 80 | 80 | 0.8 | no | 0.9 | 0.9 | 0.81
O01 | Půdorys 5.NP | 4 | 2.4 | WINDOW | 0 | 0 | 2.2 | O01 | MainObject | SmartPartCompressed | Izolační trojsklo 4-18-4-18-4 Ug 0,5 | 100 | 3.0 | Dřevěný rám 92 mm | Dřevěný lepený eurohranol | Bílý lak | Dřevěný lepený eurohranol | Okenní klika | není | Celoobvodové kování s pětibodovým uzávěrem | Jednokřídlové okno otevíravé a sklápěcí | 1852Obj0000006105 | Kus | Okno - objekt+SmartPart | 7.98 | 5 | 100 | 5 | 0.8 | no | 4 | 2.4 | 9.6
O01 | Půdorys 6.NP | 1.85 | 2.4 | WINDOW | 0 | 0 | 2.2 | O01 | MainObject | SmartPartCompressed | Izolační trojsklo 4-18-4-18-4 Ug 0,5 | 100 | 3.0 | Dřevěný rám 92 mm | Dřevěný lepený eurohranol | Bílý lak | Dřevěný lepený eurohranol | Okenní klika | není | Celoobvodové kování s pětibodovým uzávěrem | Jednokřídlové okno otevíravé a sklápěcí | 1952Obj0000001079 | Kus | Okno - objekt+SmartPart | 3.03449 | 20 | 75 | 150 | 0.8 | no | 1.85 | 2.4 | 4.08

# IfcZone (4)
NEMSOK - Jednotka: m3; Název_objektu: Skupina místností
Name | Označení | Allright_Stavebni_dil_ID
ČÁST A | ČÁST A | 1369Skm0000000674
ČÁST B | ČÁST B | 1369Skm0000000725
KAVÁRNA | KAVÁRNA | 1469Skm0000000645
URGENT | URGENT | 1469Skm0000001425
